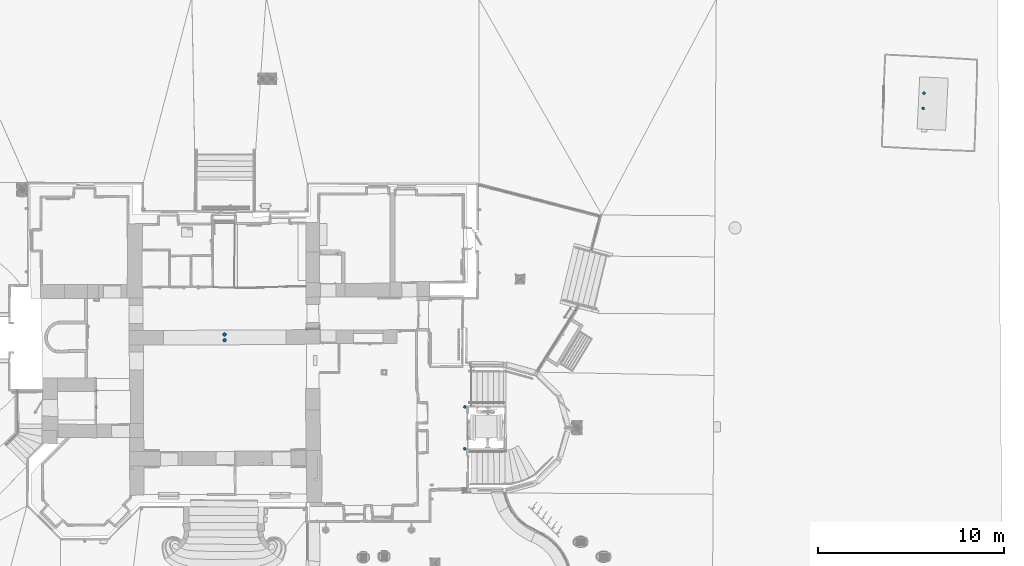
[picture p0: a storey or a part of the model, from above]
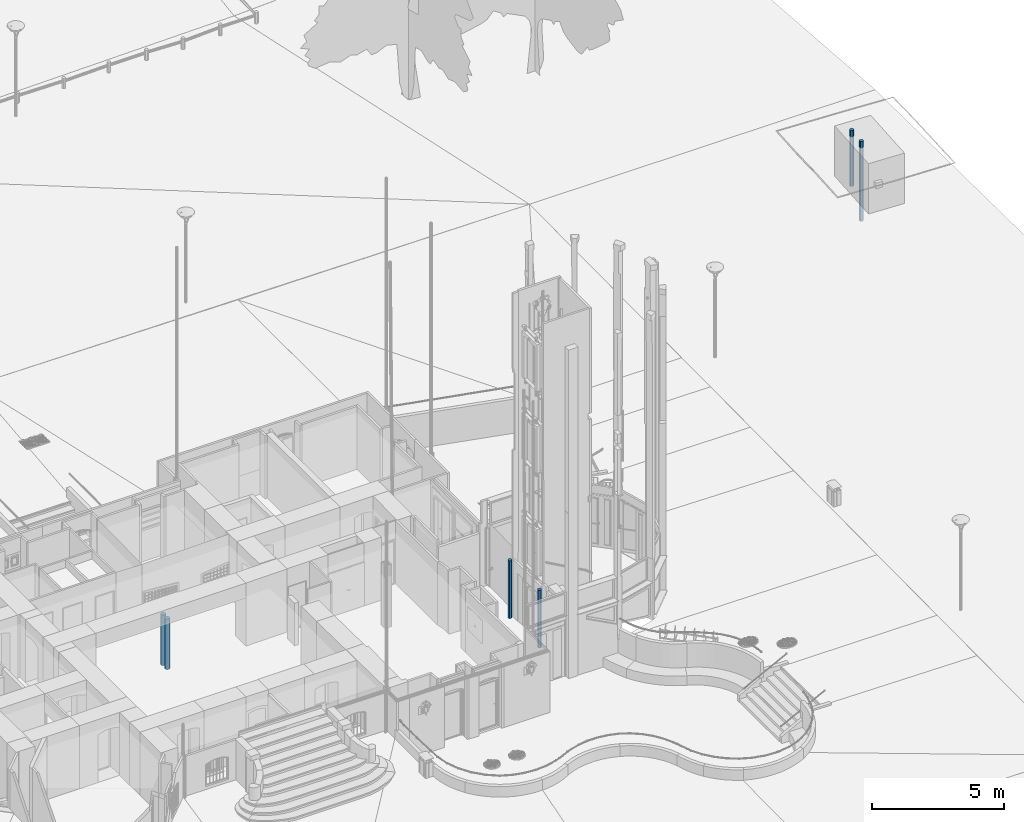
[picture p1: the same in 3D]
Properties of the parts of a building model (IFC2X3), part 1 of 37

# File
Description: ViewDefinition [CoordinationView_V2.0, QuantityTakeOffAddOnView]
File name: C:\Users\olivi\AppData\Local\Temp\EdificiusTmpDirDocs\DOC_739544-55453695\GUEUGNON Chateau d'Aux_2025 10 20.ifc
Time: 2025-10-20T15:24:24
Author: ingrid@planinsphere.com
Organization: Plan'In Sphère
Written by: ACCA_IFC.dll Version 500
Made in: ACCA Software S.p.A. - Edificius usBIM(o)

# IfcProject, GUEUGNON Chateau d'Aux_2025 10 14
IFC_PSET_Project - version: 2

# IfcSite, Default Site
RefLatitude: 0, 0, 0, 0; RefLongitude: 0, 0, 0, 0; RefElevation: 0 cm; Group: ...de matériaux et couleurs = Google Maps; ...de matériaux et couleurs - 1 = Terrain (01)
__RECOGNIZE__ - ID: 14967; TPLG: 1776; TPLG_OD: 1776; GENERATE: 1
CTLG_EXTERNAL_LINK - 0, DocType: 2; 0, Tag: 0; 0, Crc: 875694324; 1, DocType: 2; 1, Tag: 1; 1, Crc: -1747000580
IFC_PSET_PolygonOffset - polygonOffsetFactor: 2; polygonOffsetUnits: 2
IFC_Pset_Caractéristiques - ID: 14967; Numérotation: 01; Numéro niveau: 01; Titre niveau: Conception (1)
IFC_Pset_Données Métré - Volume Fouilles: 0 cm3; Volume Remblai: 0 cm3

# IfcBuildingStorey (8)
In: Default Building
Name | Description | Elevation (cm) | StateFlags | NominalHeight (cm)
TERRAIN | TERRAIN 2228 | -491.4 | 1 | 100
Fondation | Fondation 1046 | -391.4 | 2 | 100
Rez-de-Jardin | Rez-de-Jardin 15545 | -291.4 | 0 | 291.4
Rez-de-chaussée | Rez-de-chaussée 1047 | 0 | 0 | 477.795
Niveau 1 | Niveau 1 2343 | 477.795 | 0 | 376.115
Niveau 2 | Niveau 2 13545 | 853.91 | 0 | 235
Mezzanine | Mezzanine 49003 | 1088.91 | 0 | 279.702
Couverture | Couverture 2134 | 1368.61 | 4 | 0

# IfcSpace (78)
__RECOGNIZE__ - TPLG: 248; TPLG_OD: 9007; GENERATE: 1
CTLG_EXTERNAL_LINK - 0, DocType: 2; 0, Tag: 0; 0, Crc: -1342655586
IFC_PSET_PolygonOffset - polygonOffsetFactor: 1; polygonOffsetUnits: 1
IFC_Pset_Géométrie - Volume 3D: 0 cm3
IFC_Pset_Système de Référence Altimétrique_SUPÉRIEUR - delta: 0 cm; sous Niveau: <aucun>
IFC_Pset_Système de Référence Altimétrique_INFÉRIEUR - sous Niveau: <aucun>
IFC_Pset_Matériaux - Plancher: Pièce
Group: ...de matériaux et couleurs = Pièce
Name | In | Description = LongName = Nom = Reference | __RECOGNIZE__, ID = IFC_Pset_Caractéristiques, ID | Numérotation | Numéro niveau | Titre niveau | Aire (cm2) = Surface du Plafond (cm2) | Surface Nette (cm2) | Périmètre (cm) | Volume (cm3) | Hauteur (cm) = NominalHeight (cm) | Surface vitrée (cm2) | Rapport aéro-éclairant | Nombre de fenêtres | Nombre de portes | IFC_Pset_Système de Référence Altimétrique_SUPÉRIEUR, NIVEAU | IFC_Pset_Système de Référence Altimétrique_INFÉRIEUR, NIVEAU | delta (cm) | Périmètre du Plafond (cm) | GrossPlannedArea (cm2) = GrossFloorArea (cm2) = GrossCeilingArea (cm2) | GrossVolume (cm3) | GrossPerimeter (cm) | GrossWallArea (cm2) | NetWallArea (cm2)
Pièce 778369 | Rez-de-Jardin | PALIER ASC. RDJ | 778369 | 75 | 02 | Rez-de-Jardin | 177600 | 177200 | 3397.91 | 32930000 | 185.4 | 23975.2 | 0.135 | 2 | 3 | HAUT Rez-de-Jardin (Rez-de-chaussée 1047) | Rez-de-Jardin (Rez-de-Jardin 15545) | 106 | 3397.9 | 177606 | 32928213 | 3090.21 | 577951 | 362114
Pièce 590590 | Rez-de-Jardin | RANGEMENT 4 | 590590 | 69 | 02 | Rez-de-Jardin | 27300 | 27300 | 640.296 | 7940000 | 291.4 | 0 | 0 | 0 | 1 | HAUT Rez-de-Jardin (Rez-de-chaussée 1047) | Rez-de-Jardin (Rez-de-Jardin 15545) | 0 | 640.3 | 27251.4 | 7941082 | 640.296 | 142036 | 125761
Pièce 69640 | Rez-de-Jardin | LOCAL TECH.1 | 69640 | 18 | 02 | Rez-de-Jardin | 60200 | 60200 | 1158.9 | 17530000 | 291.4 | 6481.79 | 0.108 | 1 | 1 | HAUT Rez-de-Jardin (Rez-de-chaussée 1047) | Rez-de-Jardin (Rez-de-Jardin 15545) | 0 | 1158.9 | 60165.7 | 17532315 | 1158.9 | 335148 | 311362
Pièce 69641 | Rez-de-Jardin | WC2 | 69641 | 19 | 02 | Rez-de-Jardin | 17200 | 17200 | 533.931 | 5000000 | 291.4 | 0 | 0 | 0 | 1 | HAUT Rez-de-Jardin (Rez-de-chaussée 1047) | Rez-de-Jardin (Rez-de-Jardin 15545) | 0 | 533.9 | 17162.3 | 5001105 | 533.931 | 155577 | 138075
Pièce 69639 | Rez-de-Jardin | SALLE D'ACTIVITE 3 | 69639 | 17 | 02 | Rez-de-Jardin | 225300 | 225300 | 2055.74 | 65660000 | 291.4 | 21275.9 | 0.094 | 2 | 1 | HAUT Rez-de-Jardin (Rez-de-chaussée 1047) | Rez-de-Jardin (Rez-de-Jardin 15545) | 0 | 2055.7 | 225337 | 65663398 | 2055.74 | 577256 | 534926
Pièce 69642 | Rez-de-Jardin | WC3 | 69642 | 20 | 02 | Rez-de-Jardin | 26800 | 26800 | 663.262 | 7820000 | 291.4 | 0 | 0 | 0 | 1 | HAUT Rez-de-Jardin (Rez-de-chaussée 1047) | Rez-de-Jardin (Rez-de-Jardin 15545) | 0 | 663.3 | 26838.3 | 7820679 | 663.262 | 190308 | 170340
Pièce 72407 | Rez-de-Jardin | COULOIR 2 | 72407 | 33 | 02 | Rez-de-Jardin | 17400 | 17400 | 530.801 | 5070000 | 291.4 | 0 | 0 | 0 | 2 | HAUT Rez-de-Jardin (Rez-de-chaussée 1047) | Rez-de-Jardin (Rez-de-Jardin 15545) | 0 | 530.8 | 17408.2 | 5072766 | 530.801 | 154675 | 117405
Pièce 73199 | Rez-de-Jardin | LOCAL ELEC. | 73199 | 34 | 02 | Rez-de-Jardin | 15100 | 15100 | 502.217 | 4400000 | 291.4 | 0 | 0 | 0 | 1 | HAUT Rez-de-Jardin (Rez-de-chaussée 1047) | Rez-de-Jardin (Rez-de-Jardin 15545) | 0 | 502.2 | 15087.3 | 4396448 | 502.217 | 146343 | 110678
Pièce 72126 | Rez-de-Jardin | SALLE D'ACTIVITES 2 | 72126 | 31 | 02 | Rez-de-Jardin | 752400 | 751700 | 3962.15 | 219240000 | 291.4 | 44445.2 | 0.059 | 2 | 4 | HAUT Rez-de-Jardin (Rez-de-chaussée 1047) | Rez-de-Jardin (Rez-de-Jardin 15545) | 0 | 3962.2 | 752357 | 219237072 | 3451.56 | 1075218 | 869430
Pièce 72386 | Rez-de-Jardin | RANGEMENT 1 | 72386 | 32 | 02 | Rez-de-Jardin | 56800 | 56800 | 1056.47 | 16560000 | 291.4 | 35324.8 | 0.622 | 3 | 0 | HAUT Rez-de-Jardin (Rez-de-chaussée 1047) | Rez-de-Jardin (Rez-de-Jardin 15545) | 0 | 1056.5 | 56830.8 | 16560509 | 1056.47 | 284682 | 249357
Pièce 73240 | Rez-de-Jardin | COULOIR 5 | 73240 | 35 | 02 | Rez-de-Jardin | 31000 | 31000 | 704.007 | 9030000 | 291.4 | 0 | 0 | 0 | 1 | HAUT Rez-de-Jardin (Rez-de-chaussée 1047) | Rez-de-Jardin (Rez-de-Jardin 15545) | 0 | 704 | 30973.1 | 9025578 | 704.007 | 205148 | 125032
Pièce 77719 | Rez-de-Jardin | ZONE 1 | 77719 | 36 | 02 | Rez-de-Jardin | 220500 | 219900 | 6271.23 | 64240000 | 291.4 | 38357.6 | 0.174 | 3 | 1 | HAUT Rez-de-Jardin (Rez-de-chaussée 1047) | Rez-de-Jardin (Rez-de-Jardin 15545) | 0 | 6271.2 | 220466 | 64243867 | 5943.92 | 1734658 | 1611235
Pièce 78714 | Rez-de-Jardin | COULOIR 3 | 78714 | 37 | 02 | Rez-de-Jardin | 44600 | 44600 | 550.856 | 13010000 | 291.4 | 0 | 0 | 0 | 2 | HAUT Rez-de-Jardin (Rez-de-chaussée 1047) | Rez-de-Jardin (Rez-de-Jardin 15545) | 0 | 550.9 | 44639.8 | 13008065 | 550.856 | 285265 | 242583
Pièce 72125 | Rez-de-Jardin | COULOIR 4 | 72125 | 30 | 02 | Rez-de-Jardin | 95300 | 95300 | 1334.77 | 27780000 | 291.4 | 0 | 0 | 0 | 2 | HAUT Rez-de-Jardin (Rez-de-chaussée 1047) | Rez-de-Jardin (Rez-de-Jardin 15545) | 0 | 1334.8 | 95343 | 27782979 | 1334.77 | 384636 | 263139
Pièce 69646 | Rez-de-Jardin | COULOIR 1 | 69646 | 23 | 02 | Rez-de-Jardin | 92300 | 92300 | 1399.65 | 26890000 | 291.4 | 0 | 0 | 0 | 5 | HAUT Rez-de-Jardin (Rez-de-chaussée 1047) | Rez-de-Jardin (Rez-de-Jardin 15545) | 0 | 1399.6 | 92283.6 | 26891473 | 1399.65 | 396507 | 271984
Pièce 69647 | Rez-de-Jardin | SALLE D'ACTIVITES 1 | 69647 | 24 | 02 | Rez-de-Jardin | 451000 | 450200 | 3303.92 | 131430000 | 291.4 | 0 | 0 | 0 | 6 | HAUT Rez-de-Jardin (Rez-de-chaussée 1047) | Rez-de-Jardin (Rez-de-Jardin 15545) | 0 | 3303.9 | 451034 | 131431362 | 3186.56 | 832034 | 705352
Pièce 69644 | Rez-de-Jardin | LOCAL TECH.2 | 69644 | 21 | 02 | Rez-de-Jardin | 161800 | 161800 | 1777.22 | 47140000 | 291.4 | 0 | 0 | 0 | 1 | HAUT Rez-de-Jardin (Rez-de-chaussée 1047) | Rez-de-Jardin (Rez-de-Jardin 15545) | 0 | 1777.2 | 161760 | 47136934 | 1777.22 | 513166 | 481302
Pièce 69645 | Rez-de-Jardin | CUISINE | 69645 | 22 | 02 | Rez-de-Jardin | 176900 | 176900 | 1812.47 | 51540000 | 291.4 | 10335.9 | 0.058 | 1 | 2 | HAUT Rez-de-Jardin (Rez-de-chaussée 1047) | Rez-de-Jardin (Rez-de-Jardin 15545) | 0 | 1812.5 | 176859 | 51536824 | 1812.47 | 521539 | 469656
Pièce 69648 | Rez-de-Jardin | RANGEMENT 3 | 69648 | 25 | 02 | Rez-de-Jardin | 197700 | 197700 | 1816.96 | 57600000 | 291.4 | 21073.1 | 0.107 | 2 | 1 | HAUT Rez-de-Jardin (Rez-de-chaussée 1047) | Rez-de-Jardin (Rez-de-Jardin 15545) | 0 | 1817 | 197651 | 57595612 | 1816.96 | 520915 | 477846
Pièce 69651 | Rez-de-Jardin | HALL D'ENTREE | 69651 | 28 | 02 | Rez-de-Jardin | 60900 | 60900 | 1062.43 | 17740000 | 291.4 | 36449 | 0.599 | 1 | 2 | HAUT Rez-de-Jardin (Rez-de-chaussée 1047) | Rez-de-Jardin (Rez-de-Jardin 15545) | 0 | 1062.4 | 60883.1 | 17741344 | 1062.43 | 302132 | 194031
Pièce 72124 | Rez-de-Jardin | WC1 | 72124 | 29 | 02 | Rez-de-Jardin | 17300 | 17300 | 536.218 | 5050000 | 291.4 | 0 | 0 | 0 | 1 | HAUT Rez-de-Jardin (Rez-de-chaussée 1047) | Rez-de-Jardin (Rez-de-Jardin 15545) | 0 | 536.2 | 17340 | 5052868 | 536.218 | 156254 | 138194
Pièce 69649 | Rez-de-Jardin | ACCUEIL PUBLIC | 69649 | 26 | 02 | Rez-de-Jardin | 35600 | 35600 | 756.182 | 10370000 | 291.4 | 0 | 0 | 0 | 1 | HAUT Rez-de-Jardin (Rez-de-chaussée 1047) | Rez-de-Jardin (Rez-de-Jardin 15545) | 0 | 756.2 | 35581.6 | 10368492 | 756.182 | 209906 | 170097
Pièce 69650 | Rez-de-Jardin | RANGEMENT 2 | 69650 | 27 | 02 | Rez-de-Jardin | 72900 | 72900 | 1269.75 | 21250000 | 291.4 | 34974.6 | 0.48 | 3 | 1 | HAUT Rez-de-Jardin (Rez-de-chaussée 1047) | Rez-de-Jardin (Rez-de-Jardin 15545) | 0 | 1269.7 | 72927.7 | 21251158 | 1269.75 | 357255 | 300662
Pièce 773667 | Rez-de-chaussée | PARVIS RDC | 773667 | 71 | 03 | Rez-de-chaussée | 168400 | 168400 | 2188.11 | 80440000 | 477.783 | 0 | 0 | 0 | 0 | HAUT Rez-de-chaussée (Niveau 1 2343) | Rez-de-chaussée (Rez-de-chaussée 1047) | 0.0128504 | 2188.1 | 168367 | 80442995 | 2188.11 | 1035403 | 535409
Pièce 773668 | Rez-de-chaussée | PALIER ASC. RDC | 773668 | 72 | 03 | Rez-de-chaussée | 209800 | 209400 | 2489.8 | 35200000 | 167.795 | 67410.4 | 0.321 | 3 | 0 | HAUT Rez-de-chaussée (Niveau 1 2343) | Rez-de-chaussée (Rez-de-chaussée 1047) | 310 | 2489.8 | 209788 | 35201502 | 2186.67 | 400969 | 323102
Pièce 11482 | Rez-de-chaussée | WC 3 | 11482 | 13 | 03 | Rez-de-chaussée | 29000 | 29000 | 687.568 | 13880000 | 477.795 | 0 | 0 | 0 | 1 | HAUT Rez-de-chaussée (Niveau 1 2343) | Rez-de-chaussée (Rez-de-chaussée 1047) | 0 | 687.6 | 29041.3 | 13875799 | 687.568 | 241021 | 221659
Pièce 11611 | Rez-de-chaussée | RANGEMENT 1 | 11611 | 14 | 03 | Rez-de-chaussée | 45400 | 45400 | 1241.72 | 21710000 | 477.795 | 0 | 0 | 0 | 1 | HAUT Rez-de-chaussée (Niveau 1 2343) | Rez-de-chaussée (Rez-de-chaussée 1047) | 0 | 1241.7 | 45443.2 | 21712572 | 1241.72 | 501804 | 482007
Pièce 11288 | Rez-de-chaussée | SALLE D'ACTIVITE 2 | 11288 | 11 | 03 | Rez-de-chaussée | 200500 | 200500 | 1738.91 | 95780000 | 477.795 | 106073 | 0.529 | 3 | 1 | HAUT Rez-de-chaussée (Niveau 1 2343) | Rez-de-chaussée (Rez-de-chaussée 1047) | 0 | 1738.9 | 200466 | 95781710 | 1738.91 | 792242 | 657132
Pièce 11289 | Rez-de-chaussée | SALLE D'ACTIVITE1 | 11289 | 12 | 03 | Rez-de-chaussée | 391500 | 391500 | 2703.54 | 187040000 | 477.795 | 109480 | 0.28 | 3 | 2 | HAUT Rez-de-chaussée (Niveau 1 2343) | Rez-de-chaussée (Rez-de-chaussée 1047) | 0 | 2703.5 | 391466 | 187040854 | 2703.54 | 1209278 | 1044044
Pièce 42196 | Rez-de-chaussée | COULOIR 3 | 42196 | 15 | 03 | Rez-de-chaussée | 15700 | 15700 | 507.256 | 7500000 | 477.783 | 0 | 0 | 0 | 2 | HAUT Rez-de-chaussée (Niveau 1 2343) | Rez-de-chaussée (Rez-de-chaussée 1047) | 0.0128504 | 507.3 | 15699.3 | 7500869 | 507.256 | 173843 | 106140
Pièce 46048 | Rez-de-chaussée | COULOIR 2 | 46048 | 16 | 03 | Rez-de-chaussée | 105700 | 105700 | 1217.88 | 50510000 | 477.783 | 0 | 0 | 0 | 2 | HAUT Rez-de-chaussée (Niveau 1 2343) | Rez-de-chaussée (Rez-de-chaussée 1047) | 0.0128504 | 1217.9 | 105714 | 50508466 | 1217.88 | 600135 | 542391
Pièce 11287 | Rez-de-chaussée | RANGEMENT 2 | 11287 | 10 | 03 | Rez-de-chaussée | 482000 | 480600 | 23391.1 | 230300000 | 477.795 | 620857 | 1.288 | 17 | 4 | HAUT Rez-de-chaussée (Niveau 1 2343) | Rez-de-chaussée (Rez-de-chaussée 1047) | 0 | 23391.1 | 482002 | 230298425 | 23311.3 | 9950952 | 8181942
Pièce 3683 | Rez-de-chaussée | WC 1 | 3683 | 03 | 03 | Rez-de-chaussée | 15300 | 15300 | 499.002 | 7320000 | 477.795 | 0 | 0 | 0 | 1 | HAUT Rez-de-chaussée (Niveau 1 2343) | Rez-de-chaussée (Rez-de-chaussée 1047) | 0 | 499 | 15327.7 | 7323518 | 499.002 | 121755 | 107545
Pièce 11281 | Rez-de-chaussée | SALLE EXPO 3 | 11281 | 04 | 03 | Rez-de-chaussée | 334100 | 334100 | 2517.23 | 159640000 | 477.795 | 96238.4 | 0.288 | 3 | 3 | HAUT Rez-de-chaussée (Niveau 1 2343) | Rez-de-chaussée (Rez-de-chaussée 1047) | 0 | 2517.2 | 334122 | 159641772 | 2517.23 | 1088985 | 899908
Pièce 3672 | Rez-de-chaussée | SALLE EXPO 1 | 3672 | 01 | 03 | Rez-de-chaussée | 543700 | 543700 | 3172.6 | 259770000 | 477.795 | 134010 | 0.246 | 3 | 2 | HAUT Rez-de-chaussée (Niveau 1 2343) | Rez-de-chaussée (Rez-de-chaussée 1047) | 0 | 3172.6 | 543686 | 259770544 | 3172.6 | 1289069 | 989831
Pièce 3673 | Rez-de-chaussée | WC 2 | 3673 | 02 | 03 | Rez-de-chaussée | 15100 | 15100 | 495.598 | 7210000 | 477.795 | 0 | 0 | 0 | 1 | HAUT Rez-de-chaussée (Niveau 1 2343) | Rez-de-chaussée (Rez-de-chaussée 1047) | 0 | 495.6 | 15095.4 | 7212531 | 495.598 | 118201 | 103605
Pièce 11282 | Rez-de-chaussée | LOCAL TECH. | 11282 | 05 | 03 | Rez-de-chaussée | 29500 | 29500 | 692.361 | 14110000 | 477.795 | 0 | 0 | 0 | 1 | HAUT Rez-de-chaussée (Niveau 1 2343) | Rez-de-chaussée (Rez-de-chaussée 1047) | 0 | 692.4 | 29528.9 | 14108774 | 692.361 | 228056 | 210754
Pièce 11285 | Rez-de-chaussée | KITCHINETTE | 11285 | 08 | 03 | Rez-de-chaussée | 42500 | 42500 | 1016.37 | 20320000 | 477.795 | 0 | 0 | 0 | 1 | HAUT Rez-de-chaussée (Niveau 1 2343) | Rez-de-chaussée (Rez-de-chaussée 1047) | 0 | 1016.4 | 42536.2 | 20323577 | 1016.37 | 448063 | 431816
Pièce 11286 | Rez-de-chaussée | SALLE EXPO 2 | 11286 | 09 | 03 | Rez-de-chaussée | 536100 | 536100 | 3053.79 | 256170000 | 477.795 | 64189.1 | 0.12 | 2 | 2 | HAUT Rez-de-chaussée (Niveau 1 2343) | Rez-de-chaussée (Rez-de-chaussée 1047) | 0 | 3053.8 | 536144 | 256166888 | 3053.79 | 1213556 | 822975
Pièce 11283 | Rez-de-chaussée | COULOIR 1 | 11283 | 06 | 03 | Rez-de-chaussée | 124800 | 124800 | 1712.2 | 59620000 | 477.795 | 0 | 0 | 0 | 8 | HAUT Rez-de-chaussée (Niveau 1 2343) | Rez-de-chaussée (Rez-de-chaussée 1047) | 0 | 1712.2 | 124772 | 59615281 | 1712.2 | 518589 | 377767
Pièce 11284 | Rez-de-chaussée | BUREAU 1 | 11284 | 07 | 03 | Rez-de-chaussée | 242000 | 242000 | 2044.65 | 115630000 | 477.795 | 66360 | 0.274 | 2 | 1 | HAUT Rez-de-chaussée (Niveau 1 2343) | Rez-de-chaussée (Rez-de-chaussée 1047) | 0 | 2044.7 | 242009 | 115630737 | 2044.65 | 834522 | 736639
Pièce 120671 | Niveau 1 | DEGAGEMENT 1 | 120671 | 52 | 04 | Niveau 1 | 30200 | 30200 | 704.042 | 11380000 | 376.102 | 0 | 0 | 0 | 2 | HAUT Niveau 1 (Niveau 2 13545) | Niveau 1 (Niveau 1 2343) | 0.0128504 | 704 | 30246.5 | 11375764 | 703.45 | 220489 | 134417
Pièce 121282 | Niveau 1 | RANGEMENT 1 | 121282 | 53 | 04 | Niveau 1 | 15400 | 15400 | 588.48 | 5790000 | 376.102 | 0 | 0 | 0 | 1 | HAUT Niveau 1 (Niveau 2 13545) | Niveau 1 (Niveau 1 2343) | 0.0128504 | 588.5 | 15388.4 | 5787611 | 588.48 | 221327 | 182303
Pièce 115763 | Niveau 1 | KITCHINETTE | 115763 | 50 | 04 | Niveau 1 | 39700 | 39700 | 976.883 | 14930000 | 376.102 | 0 | 0 | 0 | 0 | HAUT Niveau 1 (Niveau 2 13545) | Niveau 1 (Niveau 1 2343) | 0.0128504 | 976.9 | 39697.6 | 14930339 | 976.883 | 354502 | 340722
Pièce 119074 | Niveau 1 | PALIER ETAGE 1 | 119074 | 51 | 04 | Niveau 1 | 217700 | 217700 | 2313.57 | 31590000 | 145.115 | 10632.6 | 0.049 | 2 | 0 | HAUT Niveau 1 (Niveau 2 13545) | Niveau 1 (Niveau 1 2343) | 231 | 2313.6 | 217710 | 31593018 | 2313.57 | 298027 | 283686
Pièce 121283 | Niveau 1 | POINT D'EAU | 121283 | 54 | 04 | Niveau 1 | 10200 | 10200 | 434.252 | 3820000 | 376.102 | 0 | 0 | 0 | 0 | HAUT Niveau 1 (Niveau 2 13545) | Niveau 1 (Niveau 1 2343) | 0.0128504 | 434.3 | 10165.2 | 3823142 | 434.252 | 163068 | 135056
Pièce 132686 | Niveau 1 | RANGEMENT 2 | 132686 | 55 | 04 | Niveau 1 | 50600 | 50600 | 909.567 | 19030000 | 376.102 | 13170.7 | 0.26 | 1 | 1 | HAUT Niveau 1 (Niveau 2 13545) | Niveau 1 (Niveau 1 2343) | 0.0128504 | 909.6 | 50604.9 | 19032630 | 909.567 | 342061 | 312098
Pièce 132687 | Niveau 1 | DEGAGEMENT 2 | 132687 | 56 | 04 | Niveau 1 | 39700 | 39700 | 890.582 | 5660000 | 142.615 | 0 | 0 | 0 | 0 | HAUT Niveau 1 (Niveau 2 13545) | Niveau 1 (Niveau 1 2343) | 233.5 | 890.6 | 39713.5 | 5663747 | 890.582 | 126227 | 126227
Pièce 103198 | Niveau 1 | COULOIR 2 | 103198 | 49 | 04 | Niveau 1 | 179400 | 179400 | 2763.26 | 67460000 | 376.102 | 35704.2 | 0.199 | 2 | 9 | HAUT Niveau 1 (Niveau 2 13545) | Niveau 1 (Niveau 1 2343) | 0.0128504 | 2763.3 | 179370 | 67461278 | 2763.26 | 823066 | 550650
Pièce 95094 | Niveau 1 | BUREAU 2 | 95094 | 42 | 04 | Niveau 1 | 129100 | 129100 | 1478.23 | 48550000 | 376.102 | 21276.3 | 0.165 | 1 | 3 | HAUT Niveau 1 (Niveau 2 13545) | Niveau 1 (Niveau 1 2343) | 0.0128504 | 1478.2 | 129078 | 48546639 | 1478.23 | 553756 | 477295
Pièce 95095 | Niveau 1 | BUREAU 1 | 95095 | 43 | 04 | Niveau 1 | 241000 | 241000 | 2044.25 | 90620000 | 376.102 | 43743.4 | 0.182 | 2 | 1 | HAUT Niveau 1 (Niveau 2 13545) | Niveau 1 (Niveau 1 2343) | 0.0128504 | 2044.2 | 240955 | 90623654 | 2044.26 | 752676 | 663531
Pièce 95092 | Niveau 1 | WC 3 | 95092 | 40 | 04 | Niveau 1 | 15700 | 15700 | 506.684 | 5900000 | 376.102 | 0 | 0 | 0 | 1 | HAUT Niveau 1 (Niveau 2 13545) | Niveau 1 (Niveau 1 2343) | 0.0128504 | 506.7 | 15678.2 | 5896588 | 506.684 | 137659 | 122475
Pièce 95093 | Niveau 1 | RESERVE BIBLIOTHEQUE | 95093 | 41 | 04 | Niveau 1 | 389800 | 389800 | 2764.99 | 146600000 | 376.102 | 70362.1 | 0.181 | 3 | 1 | HAUT Niveau 1 (Niveau 2 13545) | Niveau 1 (Niveau 1 2343) | 0.0128504 | 2765 | 389794 | 146602338 | 2764.99 | 1025225 | 913486
Pièce 95096 | Niveau 1 | SALLE D'ACTIVITE 3 | 95096 | 44 | 04 | Niveau 1 | 192400 | 192400 | 1597.17 | 72360000 | 376.102 | 60243.9 | 0.313 | 3 | 1 | HAUT Niveau 1 (Niveau 2 13545) | Niveau 1 (Niveau 1 2343) | 0.0128504 | 1597.2 | 192406 | 72364172 | 1597.17 | 599627 | 508114
Pièce 95099 | Niveau 1 | COULOIR 1 | 95099 | 47 | 04 | Niveau 1 | 112100 | 112100 | 1559.57 | 42180000 | 376.102 | 0 | 0 | 0 | 5 | HAUT Niveau 1 (Niveau 2 13545) | Niveau 1 (Niveau 1 2343) | 0.0128504 | 1559.6 | 112143 | 42177385 | 1559.57 | 521442 | 348595
Pièce 103197 | Niveau 1 | BUREAU 3 | 103197 | 48 | 04 | Niveau 1 | 202600 | 202600 | 2008.11 | 76200000 | 376.102 | 68975.5 | 0.34 | 4 | 2 | HAUT Niveau 1 (Niveau 2 13545) | Niveau 1 (Niveau 1 2343) | 0.0128504 | 2008.1 | 202613 | 76203241 | 2008.11 | 752930 | 637268
Pièce 95097 | Niveau 1 | SALLE D'ACTIVITE 2 | 95097 | 45 | 04 | Niveau 1 | 525800 | 525800 | 2969.7 | 197750000 | 376.102 | 130304 | 0.248 | 5 | 4 | HAUT Niveau 1 (Niveau 2 13545) | Niveau 1 (Niveau 1 2343) | 0.0128504 | 2969.7 | 525799 | 197754079 | 2969.7 | 1039293 | 818044
Pièce 95098 | Niveau 1 | SALLE D'ACTIVITE 1 | 95098 | 46 | 04 | Niveau 1 | 351400 | 351400 | 2724.83 | 132150000 | 376.102 | 74197.6 | 0.211 | 3 | 4 | HAUT Niveau 1 (Niveau 2 13545) | Niveau 1 (Niveau 1 2343) | 0.0128504 | 2724.8 | 351356 | 132145665 | 2724.83 | 950003 | 699752
Pièce 774971 | Niveau 1 | BALCON | 774971 | 73 | 04 | Niveau 1 | 168500 | 168500 | 2193.94 | 15350000 | 91.115 | 0 | 0 | 0 | 0 | HAUT Niveau 1 (Niveau 2 13545) | Niveau 1 (Niveau 1 2343) | 285 | 2193.9 | 168452 | 15348500 | 2193.94 | 198583 | 161113
Pièce 756289 | Niveau 1 | PALIER ASC. R1 | 756289 | 70 | 04 | Niveau 1 | 203800 | 203400 | 2441.27 | 76660000 | 376.102 | 160746 | 0.789 | 3 | 0 | HAUT Niveau 1 (Niveau 2 13545) | Niveau 1 (Niveau 1 2343) | 0.0128504 | 2441.3 | 203826 | 76659396 | 2141 | 922903 | 661538
Pièce 95090 | Niveau 1 | WC 1 | 95090 | 38 | 04 | Niveau 1 | 29400 | 29400 | 693.73 | 11040000 | 376.102 | 0 | 0 | 0 | 1 | HAUT Niveau 1 (Niveau 2 13545) | Niveau 1 (Niveau 1 2343) | 0.0128504 | 693.7 | 29361.7 | 11042993 | 693.73 | 220224 | 199908
Pièce 95091 | Niveau 1 | WC 2 | 95091 | 39 | 04 | Niveau 1 | 16300 | 16300 | 515.818 | 6150000 | 376.102 | 0 | 0 | 0 | 1 | HAUT Niveau 1 (Niveau 2 13545) | Niveau 1 (Niveau 1 2343) | 0.0128504 | 515.8 | 16348.8 | 6148829 | 515.818 | 140976 | 125792
Pièce 152177 | Niveau 2 | WC 1 | 152177 | 57 | 05 | Niveau 2 | 29400 | 29400 | 692.673 | 6900000 | 235 | 0 | 0 | 0 | 1 | HAUT Niveau 2 (Mezzanine 49003) | Niveau 2 (Niveau 2 13545) | 3.55271e-13 | 692.7 | 29360.6 | 6899731 | 692.673 | 143901 | 124147
Pièce 152178 | Niveau 2 | WC 2 | 152178 | 58 | 05 | Niveau 2 | 16600 | 16600 | 519.931 | 460000 | 27.7035 | 0 | 0 | 0 | 0 | HAUT Niveau 2 (Mezzanine 49003) | Niveau 2 (Niveau 2 13545) | 207.296 | 519.9 | 16554.7 | 458624 | 519.931 | 3555.55 | 3555.55
Pièce 152179 | Niveau 2 | WC 3 | 152179 | 59 | 05 | Niveau 2 | 16200 | 16200 | 514.297 | 450000 | 27.7035 | 0 | 0 | 0 | 0 | HAUT Niveau 2 (Mezzanine 49003) | Niveau 2 (Niveau 2 13545) | 207.296 | 514.3 | 16154.1 | 447527 | 514.297 | 4747.29 | 4747.29
Pièce 777386 | Niveau 2 | PALIER ASC N2 | 777386 | 74 | 05 | Niveau 2 | 256500 | 256100 | 3150.24 | 60270000 | 235 | 103325 | 0.403 | 3 | 2 | HAUT Niveau 2 (Mezzanine 49003) | Niveau 2 (Niveau 2 13545) | 0 | 3150.2 | 256473 | 60271045 | 2841.49 | 696991 | 544657
Pièce 175456 | Niveau 2 | BUREAU | 175456 | 62 | 05 | Niveau 2 | 232700 | 232700 | 1933.4 | 1630000 | 7 | 0 | 0 | 0 | 0 | HAUT Niveau 2 (Mezzanine 49003) | Niveau 2 (Niveau 2 13545) | 228 | 1933.4 | 232711 | 1628975 | 1942.85 | 36599.3 | 36599.3
Pièce 175457 | Niveau 2 | STOCKAGE | 175457 | 63 | 05 | Niveau 2 | 194700 | 194700 | 1704.92 | 45760000 | 235 | 31187.6 | 0.16 | 2 | 1 | HAUT Niveau 2 (Mezzanine 49003) | Niveau 2 (Niveau 2 13545) | 3.55271e-13 | 1704.9 | 194740 | 45763972 | 1704.92 | 392531 | 345197
Pièce 152383 | Niveau 2 | COULOIR 1 | 152383 | 60 | 05 | Niveau 2 | 155500 | 155500 | 2361.28 | 36540000 | 235 | 20168.3 | 0.13 | 1 | 7 | HAUT Niveau 2 (Mezzanine 49003) | Niveau 2 (Niveau 2 13545) | 3.55271e-13 | 2361.3 | 155510 | 36544852 | 2361.32 | 446852 | 288865
Pièce 152875 | Niveau 2 | SALLE 2 | 152875 | 61 | 05 | Niveau 2 | 381300 | 381300 | 2713.69 | 89620000 | 235 | 32029.3 | 0.084 | 2 | 2 | HAUT Niveau 2 (Mezzanine 49003) | Niveau 2 (Niveau 2 13545) | 3.55271e-13 | 2713.7 | 381345 | 89616086 | 2713.69 | 591999 | 505296
Pièce 176757 | Niveau 2 | KITCHINETTE | 176757 | 64 | 05 | Niveau 2 | 46100 | 46100 | 1034.88 | 10830000 | 235 | 0 | 0 | 0 | 0 | HAUT Niveau 2 (Mezzanine 49003) | Niveau 2 (Niveau 2 13545) | 3.55271e-13 | 1034.9 | 46087.5 | 10830571 | 1034.88 | 221082 | 205742
Pièce 176921 | Niveau 2 | PALIER ETAGE 2 | 176921 | 65 | 05 | Niveau 2 | 58800 | 58700 | 925.654 | 13810000 | 235 | 8416.86 | 0.143 | 2 | 1 | HAUT Niveau 2 (Mezzanine 49003) | Niveau 2 (Niveau 2 13545) | 3.55271e-13 | 925.7 | 58750.9 | 13806459 | 916.723 | 268450 | 240201
Pièce 177562 | Niveau 2 | SALLE 1 | 177562 | 66 | 05 | Niveau 2 | 1810200 | 1775100 | 10677 | 18100000 | 10 | 0 | 0 | 0 | 0 | HAUT Niveau 2 (Mezzanine 49003) | Niveau 2 (Niveau 2 13545) | 225 | 10677 | 1810222 | 18102217 | 8689.91 | 99793.6 | 99793.6
Pièce 2032055 | Mezzanine | SALLE 3 | 2032055 | 78 | 06 | Mezzanine | 138300 | 138200 | 349.171 | 38690000 | 279.702 | 0 | 0 | 0 | 0 | HAUT Mezzanine (Couverture 2134) | Mezzanine (Mezzanine 49003) | 0 | 349.2 | 138320 | 38688549 | 0 | 489057 | 489057
Pièce 2041841 | Mezzanine | SALLE 4 | 2041841 | 79 | 06 | Mezzanine | 41900 | 41900 | 580.689 | 9620000 | 229.702 | 0 | 0 | 0 | 0 | HAUT Mezzanine (Couverture 2134) | Mezzanine (Mezzanine 49003) | 50 | 580.7 | 41890.6 | 9622368 | 580.689 | 148029 | 148029
Pièce 2027983 | Mezzanine | SALLE 1 | 2027983 | 76 | 06 | Mezzanine | 467800 | 467100 | 2939.37 | 130850000 | 279.702 | 0 | 0 | 0 | 1 | HAUT Mezzanine (Couverture 2134) | Mezzanine (Mezzanine 49003) | 0 | 2939.4 | 467801 | 130845064 | 2653.83 | 540788 | 523562
Pièce 2032054 | Mezzanine | SALLE 2 | 2032054 | 77 | 06 | Mezzanine | 175800 | 175200 | 1872.93 | 40730000 | 231.702 | 0 | 0 | 0 | 6 | HAUT Mezzanine (Couverture 2134) | Mezzanine (Mezzanine 49003) | 48 | 1872.9 | 175788 | 40730616 | 1589.51 | 312706 | 263550
Pièce 226787 | Mezzanine | LOCAL TECHN. | 226787 | 68 | 06 | Mezzanine | 86600 | 86400 | 1203.68 | 24230000 | 279.702 | 0 | 0 | 0 | 1 | HAUT Mezzanine (Couverture 2134) | Mezzanine (Mezzanine 49003) | 3.55271e-13 | 1203.7 | 86628.2 | 24230108 | 1000.98 | 196624 | 180657

# IfcBeam: 120x220 (2)
In: Niveau 2
Type - Material: Chêne
Description: Poutre; Group: ...de sections pour tiges = 120x220; ...de matériaux et couleurs = Chêne
__RECOGNIZE__ - TPLG: 210; TPLG_OD: 501; GENERATE: 1; Section_TypeForm: 0; AngleRotaz: 0; Section, Section_NumItems: 1; Section, Section_Item 0, Section_ID: 150; Section, Section_Item 0, Section_Desc: 120,00x220,00; Section, Section_Item 0, Section_Categ: 3; Section, Section_Item 0, Section_Tipo: 0; Section, Section_Item 0, Section_Base: 0.12; Section, Section_Item 0, Section_H: 0.22; Section, Section_Item 0, Section_DistPrfX: 0; Section, Section_Item 0, Section_DistPrfY: 0; Section, Section_Item 0, Section_DispInPianta: 0; Section, Section_Item 0, Section_TipoForma: 0; Section, Section_Item 0, Section_AngleRot: 0; Section, Section_Item 0, Section_BrcX: 0; Section, Section_Item 0, Section_BrcY: 0
CTLG_EXTERNAL_LINK - 0, DocType: 6; 0, Tag: -10; 0, Crc: -2138622633; 1, DocType: 2; 1, Tag: 0; 1, Crc: -1156274542
IFC_PSET_PolygonOffset - polygonOffsetFactor: 2; polygonOffsetUnits: 2
IFC_Pset_Alignment - Alignment_Sez: 0; Alignment_Poly: 0; Alignment_NODO_CLC: 0; Alignment_C_FC_SUP: 0
IFC_Pset_Caractéristiques - Numéro niveau: 05; Titre niveau: Niveau 2; Coupe: 120x220
IFC_Pset_Géométrie - Rotation: 0 deg
IFC_Pset_Géométrie_P1 (POINT initial) - Cote: -5 cm
IFC_Pset_Géométrie_P2 (POINT final) - Cote: -5 cm
IFC_Pset_Système de Référence Altimétrique_SUPÉRIEUR - NIVEAU: HAUT Niveau 2 (Mezzanine 49003); delta (P1): -5 cm; delta (P2): -5 cm; sous Niveau: <aucun>
IFC_Pset_Données Métré - Surface de la Section: 300 cm2; Base Section: 12 cm; Hauteur Section: 22 cm; Diamètre Section: 0 cm
IFC_Pset_Matériaux - Principal: Chêne
Pset_BeamCommon - Reference: 120x220 (..\Section rectangulaire\)
BaseQuantities - CrossSectionArea: 264 cm2
Name | __RECOGNIZE__, ID = IFC_Pset_Caractéristiques, ID | Alignment_Nodo | Alignment_TS | Numérotation | IFC_Pset_Géométrie_P1 (POINT initial), Longueur (cm) = IFC_Pset_Géométrie_P2 (POINT final), Longueur (cm) = Span (cm) = NominalLength (cm) | IFC_Pset_Géométrie_P1 (POINT initial), Angle XY (deg) | IFC_Pset_Géométrie_P2 (POINT final), Angle XY (deg) | Surface (latérale) (cm2) | Volume (cm3) | Slope (deg) | OuterSurfaceArea (cm2) | TotalSurfaceArea (cm2) | GrossVolume (cm3) = NetVolume (cm3)
Poutre 220051 | 220051 | 3 | 1 | 002 | 816.536 | 0.415524 | 180.416 | 55500 | 220000 | 0 | 55524.4 | 56052.4 | 215565
Poutre 219733 | 219733 | 0 | 0 | 001 | 905.45 | 0.492415 | 180.492 | 61600 | 240000 | 2.20695e-32 | 61570.6 | 62098.6 | 239039

# IfcBeam: 120x220, Poutre 1819848
In: Mezzanine
Type - Material: Eyong
Description: Poutre; Group: ...de matériaux et couleurs = Eyong; ...de sections pour tiges = 120x220
__RECOGNIZE__ - ID: 1819848; TPLG: 210; TPLG_OD: 501; GENERATE: 1; Section_TypeForm: 0; AngleRotaz: 0; Section, Section_NumItems: 1; Section, Section_Item 0, Section_ID: 150; Section, Section_Item 0, Section_Desc: 120,00x220,00; Section, Section_Item 0, Section_Categ: 3; Section, Section_Item 0, Section_Tipo: 0; Section, Section_Item 0, Section_Base: 0.12; Section, Section_Item 0, Section_H: 0.22; Section, Section_Item 0, Section_DistPrfX: 0; Section, Section_Item 0, Section_DistPrfY: 0; Section, Section_Item 0, Section_DispInPianta: 0; Section, Section_Item 0, Section_TipoForma: 0; Section, Section_Item 0, Section_AngleRot: 0; Section, Section_Item 0, Section_BrcX: 0; Section, Section_Item 0, Section_BrcY: 0
CTLG_EXTERNAL_LINK - 0, DocType: 2; 0, Tag: 0; 0, Crc: 1459353355; 1, DocType: 6; 1, Tag: -10; 1, Crc: -2138622633
IFC_PSET_PolygonOffset - polygonOffsetFactor: 2; polygonOffsetUnits: 2
IFC_Pset_Alignment - Alignment_Sez: 0; Alignment_Poly: 0; Alignment_Nodo: 3; Alignment_TS: 1; Alignment_NODO_CLC: 0; Alignment_C_FC_SUP: 0
IFC_Pset_Caractéristiques - ID: 1819848; Numérotation: 094; Numéro niveau: 06; Titre niveau: Mezzanine; Coupe: 120x220
IFC_Pset_Géométrie - Rotation: 0 deg
IFC_Pset_Géométrie_P1 (POINT initial) - Longueur: 336.104 cm; Cote: -66 cm; Angle XY: 0.00000170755 deg
IFC_Pset_Géométrie_P2 (POINT final) - Longueur: 336.104 cm; Cote: -272.4 cm; Angle XY: 180 deg
IFC_Pset_Système de Référence Altimétrique_SUPÉRIEUR - NIVEAU: HAUT Mezzanine (Couverture 2134); delta (P1): -66 cm; delta (P2): -272.4 cm; sous Niveau: <aucun>
IFC_Pset_Données Métré - Surface (latérale): 22900 cm2; Surface de la Section: 300 cm2; Volume: 90000 cm3; Base Section: 12 cm; Hauteur Section: 22 cm; Diamètre Section: 0 cm
IFC_Pset_Matériaux - Principal: Eyong
Pset_BeamCommon - Reference: 120x220 (..\Section rectangulaire\); Slope: -37.8863 deg; Span: 336.104 cm
BaseQuantities - NominalLength: 336.104 cm; CrossSectionArea: 264 cm2; OuterSurfaceArea: 22855.1 cm2; TotalSurfaceArea: 23383.1 cm2; GrossVolume: 88731.4 cm3; NetVolume: 88731.4 cm3

# IfcBeam: 127x127 (2)
In: Couverture
Type - Material: Aluminium mat
Description: Poutre en Acier; Group: ...de matériaux et couleurs = Aluminium mat; ...de profilés en acier = 127x127
__RECOGNIZE__ - TPLG: 214; TPLG_OD: 503; GENERATE: 1; Section_TypeForm: 0; AngleRotaz: 0.785398; Section, Section_NumItems: 1; Section, Section_Item 0, Section_ID: 258; Section, Section_Item 0, Section_Desc: 5X3-1/2; Section, Section_Item 0, Section_Categ: 2; Section, Section_Item 0, Section_Tipo: 22; Section, Section_Item 0, Section_Base: 0.127; Section, Section_Item 0, Section_H: 0.127; Section, Section_Item 0, Section_DistPrfX: 0; Section, Section_Item 0, Section_DistPrfY: 0; Section, Section_Item 0, Section_DispInPianta: 0; Section, Section_Item 0, Section_TipoForma: 0; Section, Section_Item 0, Section_AngleRot: 0; Section, Section_Item 0, Section_BrcX: 0; Section, Section_Item 0, Section_BrcY: 0
CTLG_EXTERNAL_LINK - 0, DocType: 2; 0, Tag: 0; 0, Crc: 913068333; 1, DocType: 7; 1, Tag: -10; 1, Crc: -2002251891
IFC_PSET_PolygonOffset - polygonOffsetFactor: 2; polygonOffsetUnits: 2
IFC_Pset_Alignment - Alignment_Sez: 0; Alignment_NODO_CLC: 0; Alignment_C_FC_SUP: 0
IFC_Pset_Caractéristiques - Numéro niveau: 07; Titre niveau: Couverture; Coupe: 127x127
IFC_Pset_Géométrie - Rotation: 0.785398 deg
IFC_Pset_Système de Référence Altimétrique_SUPÉRIEUR - NIVEAU: Couverture (Couverture 2134); sous Niveau: <aucun>
IFC_Pset_Données Métré - Surface de la Section: 161.3 cm2; Base Section: 12.7 cm; Hauteur Section: 12.7 cm; Diamètre Section: 0 cm
IFC_Pset_Matériaux - Principal: Aluminium mat
Pset_BeamCommon - Reference: 127x127 (..\Profilés\Rectangulaire vide arêtes vives\)
BaseQuantities - CrossSectionArea: 58.0644 cm2
Name | __RECOGNIZE__, ID = IFC_Pset_Caractéristiques, ID | Alignment_Poly | Alignment_Nodo | Alignment_TS | Numérotation | IFC_Pset_Géométrie_P1 (POINT initial), Longueur (cm) = IFC_Pset_Géométrie_P2 (POINT final), Longueur (cm) = Span (cm) = NominalLength (cm) | IFC_Pset_Géométrie_P1 (POINT initial), Cote (cm) = IFC_Pset_Géométrie_P2 (POINT final), Cote (cm) = delta (P1) (cm) = delta (P2) (cm) | IFC_Pset_Géométrie_P1 (POINT initial), Angle XY (deg) | IFC_Pset_Géométrie_P2 (POINT final), Angle XY (deg) | Surface (latérale) (cm2) | Volume (cm3) | Slope (deg) | OuterSurfaceArea (cm2) | TotalSurfaceArea (cm2) | GrossVolume (cm3) = NetVolume (cm3)
Poutre en Acier 1313591 | 1313591 | -200 | 6 | 1 | 065 | 632.487 | -182 | 90.1546 | 270.155 | 32130.3 | 36720 | -1.2424e-17 | 57834.6 | 57950.7 | 36725
Poutre en Acier 1313350 | 1313350 | 0 | -1 | 0 | 059 | 373.721 | -202 | 90.1789 | 270.179 | 17491.6 | 19990 | 0 | 34173.1 | 34289.2 | 21699.9

# IfcBeam: 130.0x160.0 (4)
In: Mezzanine
Type - Material: Eyong
Description: Poutre; Group: ...de matériaux et couleurs = Eyong; ...de sections pour tiges = 130.0x160.0
__RECOGNIZE__ - TPLG: 210; TPLG_OD: 501; GENERATE: 1; Section_TypeForm: 0; AngleRotaz: 0; Section, Section_NumItems: 1; Section, Section_Item 0, Section_ID: 174; Section, Section_Item 0, Section_Desc: 130,00x160,00; Section, Section_Item 0, Section_Categ: 3; Section, Section_Item 0, Section_Tipo: 0; Section, Section_Item 0, Section_Base: 0.13; Section, Section_Item 0, Section_H: 0.16; Section, Section_Item 0, Section_DistPrfX: 0; Section, Section_Item 0, Section_DistPrfY: 0; Section, Section_Item 0, Section_DispInPianta: 0; Section, Section_Item 0, Section_TipoForma: 0; Section, Section_Item 0, Section_AngleRot: 0; Section, Section_Item 0, Section_BrcX: 0; Section, Section_Item 0, Section_BrcY: 0
CTLG_EXTERNAL_LINK - 0, DocType: 2; 0, Tag: 0; 0, Crc: 1459353355; 1, DocType: 6; 1, Tag: -10; 1, Crc: -1011586244
IFC_PSET_PolygonOffset - polygonOffsetFactor: 2; polygonOffsetUnits: 2
IFC_Pset_Alignment - Alignment_Sez: 0; Alignment_Nodo: 3; Alignment_NODO_CLC: 0; Alignment_C_FC_SUP: 0
IFC_Pset_Caractéristiques - Numéro niveau: 06; Titre niveau: Mezzanine; Coupe: 130.0x160.0
IFC_Pset_Géométrie - Rotation: 0 deg
IFC_Pset_Système de Référence Altimétrique_SUPÉRIEUR - NIVEAU: HAUT Mezzanine (Couverture 2134); sous Niveau: <aucun>
IFC_Pset_Données Métré - Surface de la Section: 200 cm2; Base Section: 13 cm; Hauteur Section: 16 cm; Diamètre Section: 0 cm
IFC_Pset_Matériaux - Principal: Eyong
Pset_BeamCommon - Reference: 130.0x160.0 (..\Section rectangulaire\)
BaseQuantities - CrossSectionArea: 208 cm2
Name | __RECOGNIZE__, ID = IFC_Pset_Caractéristiques, ID | Alignment_Poly | Alignment_TS | Numérotation | IFC_Pset_Géométrie_P1 (POINT initial), Longueur (cm) = IFC_Pset_Géométrie_P2 (POINT final), Longueur (cm) = Span (cm) = NominalLength (cm) | IFC_Pset_Géométrie_P1 (POINT initial), Cote (cm) | IFC_Pset_Géométrie_P1 (POINT initial), Angle XY (deg) | IFC_Pset_Géométrie_P2 (POINT final), Cote (cm) = delta (P2) (cm) | IFC_Pset_Géométrie_P2 (POINT final), Angle XY (deg) | delta (P1) (cm) | Surface (latérale) (cm2) | Volume (cm3) | Slope (deg) | OuterSurfaceArea (cm2) | TotalSurfaceArea (cm2) | GrossVolume (cm3) = NetVolume (cm3)
Poutre 1819909 | 1819909 | 0 | 1 | 095 | 145.38 | -70.7481 | 4.7847 | -157 | 184.785 | -70.7481 | 8400 | 30000 | -36.3905 | 8432.05 | 8848.05 | 30239.1
Poutre 1884317 | 1884317 | -1 | 1 | 122 | 369.522 | -119.496 | 1.25345 | 200 | 181.253 | -119.496 | 21400 | 80000 | 59.8394 | 21432.2 | 21848.2 | 76860.5
Poutre 1883057 | 1883057 | -1 | 0 | 120 | 358.882 | -120 | 0 | 190 | 180 | -34.844 | 20800 | 70000 | 59.7453 | 20815.1 | 21231.1 | 74647.4
Poutre 1888246 | 1888246 | -1 | 0 | 123 | 359.935 | 190 | 0.557715 | -120 | 180.558 | -54.5349 | 20900 | 70000 | -59.459 | 20876.2 | 21292.2 | 74866.5

# IfcBeam: 140x200, Poutre 574864
In: Rez-de-Jardin
Type - Material: Béton (01)
Description: Poutre; Group: ...de matériaux et couleurs = Béton (01); ...de sections pour tiges = 140x200
__RECOGNIZE__ - ID: 574864; TPLG: 210; TPLG_OD: 501; GENERATE: 1; Section_TypeForm: 0; AngleRotaz: 0; Section, Section_NumItems: 1; Section, Section_Item 0, Section_ID: 146; Section, Section_Item 0, Section_Desc: 140,00x200,00; Section, Section_Item 0, Section_Categ: 3; Section, Section_Item 0, Section_Tipo: 0; Section, Section_Item 0, Section_Base: 0.14; Section, Section_Item 0, Section_H: 0.2; Section, Section_Item 0, Section_DistPrfX: 0; Section, Section_Item 0, Section_DistPrfY: 0; Section, Section_Item 0, Section_DispInPianta: 0; Section, Section_Item 0, Section_TipoForma: 0; Section, Section_Item 0, Section_AngleRot: 0; Section, Section_Item 0, Section_BrcX: 0; Section, Section_Item 0, Section_BrcY: 0
CTLG_EXTERNAL_LINK - 0, DocType: 2; 0, Tag: 0; 0, Crc: -1434640612; 1, DocType: 6; 1, Tag: -10; 1, Crc: 614355597
IFC_PSET_PolygonOffset - polygonOffsetFactor: 2; polygonOffsetUnits: 2
IFC_Pset_Alignment - Alignment_Sez: 0; Alignment_Poly: 0; Alignment_Nodo: 0; Alignment_TS: 0; Alignment_NODO_CLC: 0; Alignment_C_FC_SUP: 0
IFC_Pset_Caractéristiques - ID: 574864; Numérotation: 003; Numéro niveau: 02; Titre niveau: Rez-de-Jardin; Coupe: 140x200
IFC_Pset_Géométrie - Rotation: 0 deg
IFC_Pset_Géométrie_P1 (POINT initial) - Longueur: 203.636 cm; Cote: 82 cm; Angle XY: 90.1987 deg
IFC_Pset_Géométrie_P2 (POINT final) - Longueur: 203.636 cm; Cote: 82 cm; Angle XY: 270.199 deg
IFC_Pset_Système de Référence Altimétrique_SUPÉRIEUR - NIVEAU: HAUT Rez-de-Jardin (Rez-de-chaussée 1047); delta (P1): 82 cm; delta (P2): 82 cm; sous Niveau: <aucun>
IFC_Pset_Données Métré - Surface (latérale): 13800 cm2; Surface de la Section: 300 cm2; Volume: 60000 cm3; Base Section: 14 cm; Hauteur Section: 20 cm; Diamètre Section: 0 cm
IFC_Pset_Matériaux - Principal: Béton (01)
Pset_BeamCommon - Reference: 140x200 (..\Section rectangulaire\); Slope: 0 deg; Span: 203.636 cm
BaseQuantities - NominalLength: 203.636 cm; CrossSectionArea: 280 cm2; OuterSurfaceArea: 13847.2 cm2; TotalSurfaceArea: 14407.2 cm2; GrossVolume: 57018.1 cm3; NetVolume: 57018.1 cm3

# IfcBeam: 140x200 (6)
In: Mezzanine
Type - Material: Eyong
Description: Poutre; Group: ...de matériaux et couleurs = Eyong; ...de sections pour tiges = 140x200
__RECOGNIZE__ - TPLG: 210; TPLG_OD: 501; GENERATE: 1; Section_TypeForm: 0; AngleRotaz: 0; Section, Section_NumItems: 1; Section, Section_Item 0, Section_ID: 146; Section, Section_Item 0, Section_Desc: 140,00x200,00; Section, Section_Item 0, Section_Categ: 3; Section, Section_Item 0, Section_Tipo: 0; Section, Section_Item 0, Section_Base: 0.14; Section, Section_Item 0, Section_H: 0.2; Section, Section_Item 0, Section_DistPrfX: 0; Section, Section_Item 0, Section_DistPrfY: 0; Section, Section_Item 0, Section_DispInPianta: 0; Section, Section_Item 0, Section_TipoForma: 0; Section, Section_Item 0, Section_AngleRot: 0; Section, Section_Item 0, Section_BrcX: 0; Section, Section_Item 0, Section_BrcY: 0
CTLG_EXTERNAL_LINK - 0, DocType: 2; 0, Tag: 0; 0, Crc: 1459353355; 1, DocType: 6; 1, Tag: -10; 1, Crc: 614355597
IFC_PSET_PolygonOffset - polygonOffsetFactor: 2; polygonOffsetUnits: 2
IFC_Pset_Alignment - Alignment_Sez: 0; Alignment_Poly: 0; Alignment_Nodo: 0; Alignment_NODO_CLC: 0; Alignment_C_FC_SUP: 0
IFC_Pset_Caractéristiques - Numéro niveau: 06; Titre niveau: Mezzanine; Coupe: 140x200
IFC_Pset_Géométrie - Rotation: 0 deg
IFC_Pset_Système de Référence Altimétrique_SUPÉRIEUR - NIVEAU: HAUT Mezzanine (Couverture 2134); sous Niveau: <aucun>
IFC_Pset_Données Métré - Surface de la Section: 300 cm2; Base Section: 14 cm; Hauteur Section: 20 cm; Diamètre Section: 0 cm
IFC_Pset_Matériaux - Principal: Eyong
Pset_BeamCommon - Reference: 140x200 (..\Section rectangulaire\)
BaseQuantities - CrossSectionArea: 280 cm2
Name | __RECOGNIZE__, ID = IFC_Pset_Caractéristiques, ID | Alignment_TS | Numérotation | IFC_Pset_Géométrie_P1 (POINT initial), Longueur (cm) = IFC_Pset_Géométrie_P2 (POINT final), Longueur (cm) = Span (cm) = NominalLength (cm) | IFC_Pset_Géométrie_P1 (POINT initial), Cote (cm) | IFC_Pset_Géométrie_P1 (POINT initial), Angle XY (deg) | IFC_Pset_Géométrie_P2 (POINT final), Cote (cm) = delta (P2) (cm) | IFC_Pset_Géométrie_P2 (POINT final), Angle XY (deg) | delta (P1) (cm) | Surface (latérale) (cm2) | Volume (cm3) | Slope (deg) | OuterSurfaceArea (cm2) | TotalSurfaceArea (cm2) | GrossVolume (cm3) = NetVolume (cm3)
Poutre 1809122 | 1809122 | 1 | 086 | 200 | 151.355 | 91.2145 | -23.5315 | 271.215 | 151.355 | 13600 | 60000 | -60.9781 | 13600 | 14160 | 56000
Poutre 1812017 | 1812017 | 0 | 089 | 180 | -28.9731 | 91.0481 | 124.842 | 271.048 | -28.9731 | 12200 | 50000 | 58.7078 | 12240 | 12800 | 50400
Poutre 1805559 | 1805559 | 1 | 085 | 125 | -23.5315 | 91.2145 | -130 | 271.215 | -23.5315 | 8500 | 40000 | -58.4021 | 8500.01 | 9060.01 | 35000.1
Poutre 1815186 | 1815186 | 0 | 090 | 132.366 | -139 | 90 | -23.7944 | 270 | -139 | 9000 | 40000 | 60.5001 | 9000.89 | 9560.89 | 37062.5
Poutre 1810550 | 1810550 | 1 | 087 | 293.609 | 126.698 | 91.2145 | -125 | 271.215 | -27.6084 | 20000 | 80000 | -59.0099 | 19965.4 | 20525.4 | 82210.4
Poutre 1819587 | 1819587 | 0 | 091 | 350 | -139 | 90 | 165.625 | 270 | -25.9148 | 23800 | 100000 | 60.5001 | 23800 | 24360 | 98000

# IfcBeam: 150.0x150.0x25.0 (2)
In: Mezzanine
Type - Material: Eyong
Description: Poutre; Group: ...de sections pour tiges = 150.0x150.0x25.0; ...de matériaux et couleurs = Eyong
__RECOGNIZE__ - TPLG: 210; TPLG_OD: 501; GENERATE: 1; Section_TypeForm: 0; Section, Section_NumItems: 1; Section, Section_Item 0, Section_ID: 124; Section, Section_Item 0, Section_Desc: 150x150; Section, Section_Item 0, Section_Categ: 3; Section, Section_Item 0, Section_Tipo: 22; Section, Section_Item 0, Section_Base: 0.15; Section, Section_Item 0, Section_H: 0.15; Section, Section_Item 0, Section_DistPrfX: 0; Section, Section_Item 0, Section_DistPrfY: 0; Section, Section_Item 0, Section_DispInPianta: 0; Section, Section_Item 0, Section_TipoForma: 0; Section, Section_Item 0, Section_AngleRot: 0; Section, Section_Item 0, Section_BrcX: 0; Section, Section_Item 0, Section_BrcY: 0
CTLG_EXTERNAL_LINK - 0, DocType: 2; 0, Tag: 0; 0, Crc: 1459353355; 1, DocType: 6; 1, Tag: -10; 1, Crc: -603927665
IFC_PSET_PolygonOffset - polygonOffsetFactor: 2; polygonOffsetUnits: 2
IFC_Pset_Alignment - Alignment_Sez: 0; Alignment_Poly: 0; Alignment_NODO_CLC: 0; Alignment_C_FC_SUP: 0
IFC_Pset_Caractéristiques - Numéro niveau: 06; Titre niveau: Mezzanine; Coupe: 150.0x150.0x25.0
IFC_Pset_Système de Référence Altimétrique_SUPÉRIEUR - NIVEAU: HAUT Mezzanine (Couverture 2134); sous Niveau: <aucun>
IFC_Pset_Données Métré - Surface de la Section: 200 cm2; Volume: 50000 cm3; Base Section: 15 cm; Hauteur Section: 15 cm; Diamètre Section: 0 cm
IFC_Pset_Matériaux - Principal: Eyong
Pset_BeamCommon - Reference: 150.0x150.0x25.0 (..\Section rectangulaire arrondie\)
BaseQuantities - CrossSectionArea: 219.607 cm2
Name | __RECOGNIZE__, ID = IFC_Pset_Caractéristiques, ID | AngleRotaz = Rotation (deg) | Alignment_Nodo | Alignment_TS | Numérotation | IFC_Pset_Géométrie_P1 (POINT initial), Longueur (cm) = IFC_Pset_Géométrie_P2 (POINT final), Longueur (cm) = Span (cm) = NominalLength (cm) | IFC_Pset_Géométrie_P1 (POINT initial), Cote (cm) | IFC_Pset_Géométrie_P1 (POINT initial), Angle XY (deg) | IFC_Pset_Géométrie_P2 (POINT final), Cote (cm) = delta (P2) (cm) | IFC_Pset_Géométrie_P2 (POINT final), Angle XY (deg) | delta (P1) (cm) | Surface (latérale) (cm2) | Slope (deg) | OuterSurfaceArea (cm2) | TotalSurfaceArea (cm2) | GrossVolume (cm3) = NetVolume (cm3)
Poutre 1819841 | 1819841 | 0.785398 | 1 | 1 | 093 | 236.71 | -163 | 90 | -163 | 270 | -163 | 13200 | 0 | 13186.6 | 13625.8 | 51983.2
Poutre 1780034 | 1780034 | 0 | 7 | 0 | 072 | 238.741 | -272.267 | 45.8919 | -91.5108 | 225.892 | -240.739 | 13300 | 49.2113 | 13299.8 | 13739 | 52429.2

# IfcBeam: 187x300 (17)
In: Mezzanine
Type - Material: Eyong
Description: Poutre; Group: ...de matériaux et couleurs = Eyong; ...de sections pour tiges = 187x300
__RECOGNIZE__ - TPLG: 210; TPLG_OD: 501; GENERATE: 1; Section_TypeForm: 0; AngleRotaz: 0; Section, Section_NumItems: 1; Section, Section_Item 0, Section_ID: 156; Section, Section_Item 0, Section_Desc: 187x300; Section, Section_Item 0, Section_Categ: 3; Section, Section_Item 0, Section_Tipo: 0; Section, Section_Item 0, Section_Base: 0.187; Section, Section_Item 0, Section_H: 0.3; Section, Section_Item 0, Section_DistPrfX: 0; Section, Section_Item 0, Section_DistPrfY: 0; Section, Section_Item 0, Section_DispInPianta: 0; Section, Section_Item 0, Section_TipoForma: 0; Section, Section_Item 0, Section_AngleRot: 0; Section, Section_Item 0, Section_BrcX: 0; Section, Section_Item 0, Section_BrcY: 0
CTLG_EXTERNAL_LINK - 0, DocType: 2; 0, Tag: 0; 0, Crc: 1459353355; 1, DocType: 6; 1, Tag: -10; 1, Crc: 2071014828
IFC_PSET_PolygonOffset - polygonOffsetFactor: 2; polygonOffsetUnits: 2
IFC_Pset_Alignment - Alignment_Sez: 0; Alignment_Poly: 0; Alignment_NODO_CLC: 0; Alignment_C_FC_SUP: 0
IFC_Pset_Caractéristiques - Numéro niveau: 06; Titre niveau: Mezzanine; Coupe: 187x300
IFC_Pset_Géométrie - Rotation: 0 deg
IFC_Pset_Système de Référence Altimétrique_SUPÉRIEUR - NIVEAU: HAUT Mezzanine (Couverture 2134); sous Niveau: <aucun>
IFC_Pset_Données Métré - Surface de la Section: 600 cm2; Base Section: 18.7 cm; Hauteur Section: 30 cm; Diamètre Section: 0 cm
IFC_Pset_Matériaux - Principal: Eyong
Pset_BeamCommon - Reference: 187x300 (..\Section rectangulaire\)
BaseQuantities - CrossSectionArea: 561 cm2
Name | __RECOGNIZE__, ID = IFC_Pset_Caractéristiques, ID | Alignment_Nodo | Alignment_TS | Numérotation | IFC_Pset_Géométrie_P1 (POINT initial), Longueur (cm) = IFC_Pset_Géométrie_P2 (POINT final), Longueur (cm) = Span (cm) = NominalLength (cm) | IFC_Pset_Géométrie_P1 (POINT initial), Cote (cm) | IFC_Pset_Géométrie_P1 (POINT initial), Angle XY (deg) | IFC_Pset_Géométrie_P2 (POINT final), Cote (cm) = delta (P2) (cm) | IFC_Pset_Géométrie_P2 (POINT final), Angle XY (deg) | delta (P1) (cm) | Surface (latérale) (cm2) | Volume (cm3) | Slope (deg) | OuterSurfaceArea (cm2) | TotalSurfaceArea (cm2) | GrossVolume (cm3) = NetVolume (cm3)
Poutre 1717275 | 1717275 | 0 | 1 | 056 | 98.758 | -270 | 0.797217 | -268 | 180.797 | -270 | 9600 | 60000 | 1.16041 | 9619.03 | 10741 | 55403.3
Poutre 1717274 | 1717274 | 0 | 1 | 055 | 103.8 | -268 | 0.797217 | -265 | 180.797 | -268 | 10100 | 60000 | 1.65618 | 10110.1 | 11232.1 | 58231.6
Poutre 1717774 | 1717774 | 3 | 0 | 059 | 108.72 | -230 | 135.047 | -230 | 315.047 | -230 | 10600 | 60000 | 0 | 10589.3 | 11711.3 | 60991.7
Poutre 1715116 | 1715116 | 0 | 1 | 037 | 128.403 | -265 | 44.4722 | -265 | 224.472 | -265 | 12500 | 70000 | 0 | 12506.4 | 13628.4 | 72033.9
Poutre 1715126 | 1715126 | 0 | 1 | 040 | 248.1 | -265 | 0.43893 | -260 | 180.439 | -265 | 24200 | 140000 | 1.15477 | 24164.9 | 25286.9 | 139184
Poutre 1715110 | 1715110 | 0 | 1 | 035 | 498.706 | -265 | 137.137 | -265 | 317.137 | -265 | 48600 | 280000 | 0 | 48573.9 | 49695.9 | 279774
Poutre 1717252 | 1717252 | 3 | 0 | 048 | 132.733 | -260 | 46.6887 | -260 | 226.689 | -260 | 12900 | 70000 | 0 | 12928.2 | 14050.2 | 74463.1
Poutre 1717249 | 1717249 | 0 | 1 | 047 | 131.712 | -260 | 135.716 | -260 | 315.716 | -260 | 12800 | 70000 | 0 | 12828.7 | 13950.7 | 73890.3
Poutre 1715130 | 1715130 | 0 | 1 | 041 | 532.023 | -265 | 43.8998 | -260.281 | 223.9 | -265 | 51800 | 300000 | 0.508235 | 51819 | 52941 | 298465
Poutre 1716385 | 1716385 | 0 | 0 | 044 | 501.254 | -261.078 | 43.5213 | -264 | 223.521 | -261.078 | 48800 | 280000 | -0.334005 | 48822.1 | 49944.1 | 281203
Poutre 1715102 | 1715102 | 0 | 1 | 034 | 445.591 | -270 | 0.797217 | -270 | 180.797 | -270 | 43400 | 250000 | 0 | 43400.5 | 44522.5 | 249976
Poutre 1715113 | 1715113 | 0 | 0 | 036 | 404.552 | -265.576 | 90.4124 | -263 | 270.412 | -264.995 | 39400 | 230000 | 0.364878 | 39403.4 | 40525.4 | 226954
Poutre 1715216 | 1715216 | 3 | 1 | 042 | 898.572 | -270 | 0.555365 | -270 | 180.555 | -270 | 87500 | 500000 | 0 | 87520.9 | 88642.9 | 504099
Poutre 1717020 | 1717020 | 3 | 1 | 045 | 527.218 | -260 | 137.073 | -260 | 317.073 | -260 | 51400 | 300000 | 0 | 51351 | 52473 | 295769
Poutre 1717259 | 1717259 | 0 | 1 | 052 | 212.645 | -260 | 46.6694 | -260 | 226.669 | -260 | 20700 | 120000 | 0 | 20711.6 | 21833.6 | 119294
Poutre 1717170 | 1717170 | 0 | 1 | 046 | 398.333 | -260 | 90.4992 | -260 | 270.499 | -260 | 38800 | 220000 | 0 | 38797.6 | 39919.6 | 223465
Poutre 1715120 | 1715120 | 3 | 1 | 038 | 128.205 | -265 | 135.872 | -265 | 315.872 | -265 | 12500 | 70000 | 0 | 12487.2 | 13609.2 | 71922.9

# IfcBeam: 200,00x200,00x10,00 (8)
Type - Material: Eyong
Description: Poutre; Group: ...de sections pour tiges = 200,00x200,00x10,00; ...de matériaux et couleurs = Eyong
__RECOGNIZE__ - TPLG: 210; TPLG_OD: 501; GENERATE: 1; Section_TypeForm: 0; AngleRotaz: 0; Section, Section_NumItems: 1; Section, Section_Item 0, Section_ID: 118; Section, Section_Item 0, Section_Desc: 200,00x200,00x10,00; Section, Section_Item 0, Section_Categ: 3; Section, Section_Item 0, Section_Tipo: 22; Section, Section_Item 0, Section_Base: 0.2; Section, Section_Item 0, Section_H: 0.2; Section, Section_Item 0, Section_DistPrfX: 0; Section, Section_Item 0, Section_DistPrfY: 0; Section, Section_Item 0, Section_DispInPianta: 0; Section, Section_Item 0, Section_TipoForma: 0; Section, Section_Item 0, Section_AngleRot: 0; Section, Section_Item 0, Section_BrcX: 0; Section, Section_Item 0, Section_BrcY: 0
CTLG_EXTERNAL_LINK - 0, DocType: 2; 0, Tag: 0; 0, Crc: 1459353355; 1, DocType: 6; 1, Tag: -10; 1, Crc: -579435193
IFC_PSET_PolygonOffset - polygonOffsetFactor: 2; polygonOffsetUnits: 2
IFC_Pset_Alignment - Alignment_Sez: 0; Alignment_Poly: 0; Alignment_TS: 1; Alignment_NODO_CLC: 0; Alignment_C_FC_SUP: 0
IFC_Pset_Caractéristiques - Coupe: 200,00x200,00x10,00
IFC_Pset_Géométrie - Rotation: 0 deg
IFC_Pset_Système de Référence Altimétrique_SUPÉRIEUR - sous Niveau: <aucun>
IFC_Pset_Données Métré - Surface de la Section: 400 cm2; Base Section: 20 cm; Hauteur Section: 20 cm; Diamètre Section: 0 cm
IFC_Pset_Matériaux - Principal: Eyong
Pset_BeamCommon - Reference: 200,00x200,00x10,00 (..\Section rectangulaire arrondie\); Slope: 0 deg
BaseQuantities - CrossSectionArea: 399.138 cm2
Name | In | __RECOGNIZE__, ID = IFC_Pset_Caractéristiques, ID | Alignment_Nodo | Numérotation | Numéro niveau | Titre niveau | IFC_Pset_Géométrie_P1 (POINT initial), Longueur (cm) = IFC_Pset_Géométrie_P2 (POINT final), Longueur (cm) = Span (cm) = NominalLength (cm) | IFC_Pset_Géométrie_P1 (POINT initial), Cote (cm) = IFC_Pset_Géométrie_P2 (POINT final), Cote (cm) = delta (P1) (cm) = delta (P2) (cm) | IFC_Pset_Géométrie_P1 (POINT initial), Angle XY (deg) | IFC_Pset_Géométrie_P2 (POINT final), Angle XY (deg) | NIVEAU | Surface (latérale) (cm2) | Volume (cm3) | OuterSurfaceArea (cm2) | TotalSurfaceArea (cm2) | GrossVolume (cm3) = NetVolume (cm3)
Poutre 1741656 | Niveau 2 | 1741656 | 2 | 070 | 05 | Niveau 2 | 40.4042 | 12 | 0 | 180 | HAUT Niveau 2 (Mezzanine 49003) | 3100 | 20000 | 3137.66 | 3935.94 | 16126.8
Poutre 1740831 | Niveau 2 | 1740831 | 7 | 067 | 05 | Niveau 2 | 35.4914 | 12 | 46.7742 | 226.774 | HAUT Niveau 2 (Mezzanine 49003) | 2800 | 10000 | 2756.15 | 3554.43 | 14166
Poutre 1740508 | Niveau 2 | 1740508 | 1 | 066 | 05 | Niveau 2 | 47.2721 | 12 | 136.71 | 316.71 | HAUT Niveau 2 (Mezzanine 49003) | 3700 | 20000 | 3671 | 4469.28 | 18868.1
Poutre 1741368 | Niveau 2 | 1741368 | 7 | 069 | 05 | Niveau 2 | 45.5346 | 12 | 137.232 | 317.232 | HAUT Niveau 2 (Mezzanine 49003) | 3500 | 20000 | 3536.08 | 4334.35 | 18174.6
Poutre 1741092 | Niveau 2 | 1741092 | 2 | 068 | 05 | Niveau 2 | 37.484 | 12 | 43.2132 | 223.213 | HAUT Niveau 2 (Mezzanine 49003) | 2900 | 10000 | 2910.89 | 3709.16 | 14961.3
Poutre 1720691 | Niveau 2 | 1720691 | 0 | 061 | 05 | Niveau 2 | 53.8111 | 20 | 123.369 | 303.369 | HAUT Niveau 2 (Mezzanine 49003) | 4200 | 20000 | 4178.8 | 4977.07 | 21478
Poutre 1719965 | Niveau 2 | 1719965 | 1 | 060 | 05 | Niveau 2 | 38.8211 | 19 | 90 | 270 | HAUT Niveau 2 (Mezzanine 49003) | 3000 | 20000 | 3014.72 | 3813 | 15495
Poutre 1741944 | Mezzanine | 1741944 | 2 | 071 | 06 | Mezzanine | 355.567 | -235 | 45.5411 | 225.541 | HAUT Mezzanine (Couverture 2134) | 27600 | 140000 | 27612.2 | 28410.5 | 141920

# IfcBeam: 240x200 (4)
In: Niveau 2
Type - Material: Eyong
Description: Poutre; Group: ...de matériaux et couleurs = Eyong; ...de sections pour tiges = 240x200
__RECOGNIZE__ - TPLG: 210; TPLG_OD: 501; GENERATE: 1; Section_TypeForm: 0; AngleRotaz: 0; Section, Section_NumItems: 1; Section, Section_Item 0, Section_ID: 154; Section, Section_Item 0, Section_Desc: 240,00x200,00; Section, Section_Item 0, Section_Categ: 3; Section, Section_Item 0, Section_Tipo: 0; Section, Section_Item 0, Section_Base: 0.24; Section, Section_Item 0, Section_H: 0.2; Section, Section_Item 0, Section_DistPrfX: 0; Section, Section_Item 0, Section_DistPrfY: 0; Section, Section_Item 0, Section_DispInPianta: 0; Section, Section_Item 0, Section_TipoForma: 0; Section, Section_Item 0, Section_AngleRot: 0; Section, Section_Item 0, Section_BrcX: 0; Section, Section_Item 0, Section_BrcY: 0
CTLG_EXTERNAL_LINK - 0, DocType: 2; 0, Tag: 0; 0, Crc: 1459353355; 1, DocType: 6; 1, Tag: -10; 1, Crc: -1373019717
IFC_PSET_PolygonOffset - polygonOffsetFactor: 2; polygonOffsetUnits: 2
IFC_Pset_Alignment - Alignment_Sez: 0; Alignment_Poly: 0; Alignment_NODO_CLC: 0; Alignment_C_FC_SUP: 0
IFC_Pset_Caractéristiques - Numéro niveau: 05; Titre niveau: Niveau 2; Coupe: 240x200
IFC_Pset_Géométrie - Rotation: 0 deg
IFC_Pset_Géométrie_P1 (POINT initial) - Cote: 12 cm
IFC_Pset_Géométrie_P2 (POINT final) - Cote: 12 cm
IFC_Pset_Système de Référence Altimétrique_SUPÉRIEUR - NIVEAU: HAUT Niveau 2 (Mezzanine 49003); delta (P1): 12 cm; delta (P2): 12 cm; sous Niveau: <aucun>
IFC_Pset_Données Métré - Surface de la Section: 500 cm2; Base Section: 24 cm; Hauteur Section: 20 cm; Diamètre Section: 0 cm
IFC_Pset_Matériaux - Principal: Eyong
Pset_BeamCommon - Reference: 240x200 (..\Section rectangulaire\)
BaseQuantities - CrossSectionArea: 480 cm2
Name | __RECOGNIZE__, ID = IFC_Pset_Caractéristiques, ID | Alignment_Nodo | Alignment_TS | Numérotation | IFC_Pset_Géométrie_P1 (POINT initial), Longueur (cm) = IFC_Pset_Géométrie_P2 (POINT final), Longueur (cm) = Span (cm) = NominalLength (cm) | IFC_Pset_Géométrie_P1 (POINT initial), Angle XY (deg) | IFC_Pset_Géométrie_P2 (POINT final), Angle XY (deg) | Surface (latérale) (cm2) | Volume (cm3) | Slope (deg) | OuterSurfaceArea (cm2) | TotalSurfaceArea (cm2) | GrossVolume (cm3) = NetVolume (cm3)
Poutre 1739741 | 1739741 | 3 | 0 | 065 | 61.0344 | 136.785 | 316.785 | 5400 | 30000 | 0 | 5371.03 | 6331.03 | 29296.5
Poutre 1734157 | 1734157 | 3 | 1 | 062 | 49.5337 | 46.5988 | 226.599 | 4400 | 20000 | 0 | 4358.97 | 5318.97 | 23776.2
Poutre 1738207 | 1738207 | 0 | 1 | 064 | 62.805 | 45 | 225 | 5500 | 30000 | 0 | 5526.84 | 6486.84 | 30146.4
Poutre 1736344 | 1736344 | 0 | 1 | 063 | 49.1221 | 136.41 | 316.41 | 4300 | 20000 | -1.41245e-30 | 4322.75 | 5282.75 | 23578.6

# IfcBeam: 280x280 (3)
In: Couverture
Type - Material: Aluminium mat
Description: Poutre en Acier; Group: ...de matériaux et couleurs = Aluminium mat; ...de profilés en acier = 280x280
__RECOGNIZE__ - TPLG: 214; TPLG_OD: 503; GENERATE: 1; Section_TypeForm: 0; AngleRotaz: 0; Section, Section_NumItems: 1; Section, Section_Item 0, Section_ID: 252; Section, Section_Item 0, Section_Desc: 280x280; Section, Section_Item 0, Section_Categ: 2; Section, Section_Item 0, Section_Tipo: 24; Section, Section_Item 0, Section_Base: 0.28; Section, Section_Item 0, Section_H: 0.28; Section, Section_Item 0, Section_DistPrfX: 0; Section, Section_Item 0, Section_DistPrfY: 0; Section, Section_Item 0, Section_DispInPianta: 0; Section, Section_Item 0, Section_TipoForma: 0; Section, Section_Item 0, Section_AngleRot: 0; Section, Section_Item 0, Section_BrcX: 0; Section, Section_Item 0, Section_BrcY: 0
CTLG_EXTERNAL_LINK - 0, DocType: 2; 0, Tag: 0; 0, Crc: 913068333; 1, DocType: 7; 1, Tag: -10; 1, Crc: -684708269
IFC_PSET_PolygonOffset - polygonOffsetFactor: 2; polygonOffsetUnits: 2
IFC_Pset_Alignment - Alignment_Sez: 0; Alignment_Poly: -200; Alignment_TS: 0; Alignment_NODO_CLC: 0; Alignment_C_FC_SUP: 0
IFC_Pset_Caractéristiques - Numéro niveau: 07; Titre niveau: Couverture; Coupe: 280x280
IFC_Pset_Géométrie - Rotation: 0 deg
IFC_Pset_Géométrie_P1 (POINT initial) - Cote: -270 cm
IFC_Pset_Géométrie_P2 (POINT final) - Cote: -270 cm
IFC_Pset_Système de Référence Altimétrique_SUPÉRIEUR - NIVEAU: Couverture (Couverture 2134); delta (P1): -270 cm; delta (P2): -270 cm; sous Niveau: <aucun>
IFC_Pset_Données Métré - Surface de la Section: 784 cm2; Base Section: 28 cm; Hauteur Section: 28 cm; Diamètre Section: 0 cm
IFC_Pset_Matériaux - Principal: Aluminium mat
Pset_BeamCommon - Reference: 280x280 (..\Profilés\Rectangulaire\); Slope: 0 deg
BaseQuantities - CrossSectionArea: 784 cm2
Name | __RECOGNIZE__, ID = IFC_Pset_Caractéristiques, ID | Alignment_Nodo | Numérotation | IFC_Pset_Géométrie_P1 (POINT initial), Longueur (cm) = IFC_Pset_Géométrie_P2 (POINT final), Longueur (cm) = Span (cm) = NominalLength (cm) | IFC_Pset_Géométrie_P1 (POINT initial), Angle XY (deg) | IFC_Pset_Géométrie_P2 (POINT final), Angle XY (deg) | Surface (latérale) (cm2) | Volume (cm3) | OuterSurfaceArea (cm2) | TotalSurfaceArea (cm2) | GrossVolume (cm3) = NetVolume (cm3)
Poutre en Acier 1303896 | 1303896 | 0 | 057 | 146.137 | 179.791 | 359.791 | 16367.4 | 114570 | 16367.4 | 17935.4 | 114572
Poutre en Acier 1312596 | 1312596 | 0 | 058 | 624.875 | 89.7268 | 269.727 | 69986 | 489900 | 69986 | 71554 | 489902
Poutre en Acier 1303097 | 1303097 | 6 | 056 | 592.082 | 90.1294 | 270.129 | 40532.1 | 283720 | 66313.1 | 67881.1 | 464192

# IfcBeam: 2X1-5/16 (7)
In: Mezzanine
Type - Material: Aluminium mat
Description: Poutre en Acier; Group: ...de matériaux et couleurs = Aluminium mat; ...de profilés en acier = 2X1-5/16
__RECOGNIZE__ - TPLG: 214; TPLG_OD: 503; GENERATE: 1; Section_TypeForm: 0; AngleRotaz: 0; Section, Section_NumItems: 1; Section, Section_Item 0, Section_ID: 274; Section, Section_Item 0, Section_Desc: 4X2-5/16; Section, Section_Item 0, Section_Categ: 2; Section, Section_Item 0, Section_Tipo: 22; Section, Section_Item 0, Section_Base: 0.025; Section, Section_Item 0, Section_H: 0.05; Section, Section_Item 0, Section_DistPrfX: 0; Section, Section_Item 0, Section_DistPrfY: 0; Section, Section_Item 0, Section_DispInPianta: 0; Section, Section_Item 0, Section_TipoForma: 0; Section, Section_Item 0, Section_AngleRot: 0; Section, Section_Item 0, Section_BrcX: 0; Section, Section_Item 0, Section_BrcY: 0
CTLG_EXTERNAL_LINK - 0, DocType: 2; 0, Tag: 0; 0, Crc: 913068333; 1, DocType: 7; 1, Tag: -10; 1, Crc: 745588298
IFC_PSET_PolygonOffset - polygonOffsetFactor: 2; polygonOffsetUnits: 2
IFC_Pset_Alignment - Alignment_Sez: 0; Alignment_Poly: -200; Alignment_Nodo: 4; Alignment_TS: 1; Alignment_NODO_CLC: 0; Alignment_C_FC_SUP: 0
IFC_Pset_Caractéristiques - Numéro niveau: 06; Titre niveau: Mezzanine; Coupe: 2X1-5/16
IFC_Pset_Géométrie - Rotation: 0 deg
IFC_Pset_Géométrie_P1 (POINT initial) - Longueur: 44.6329 cm; Angle XY: 179.717 deg
IFC_Pset_Géométrie_P2 (POINT final) - Longueur: 44.6329 cm; Angle XY: 359.717 deg
IFC_Pset_Système de Référence Altimétrique_SUPÉRIEUR - NIVEAU: HAUT Mezzanine (Couverture 2134); sous Niveau: <aucun>
IFC_Pset_Données Métré - Surface (latérale): 669.5 cm2; Surface de la Section: 12.5 cm2; Volume: 420 cm3; Base Section: 2.5 cm; Hauteur Section: 5 cm; Diamètre Section: 0 cm
IFC_Pset_Matériaux - Principal: Aluminium mat
Pset_BeamCommon - Reference: 2X1-5/16 (..\Profilés\Rectangulaire vide arêtes vives\); Slope: 0 deg; Span: 44.6329 cm
BaseQuantities - NominalLength: 44.6329 cm; CrossSectionArea: 9.3536 cm2; OuterSurfaceArea: 1056.91 cm2; TotalSurfaceArea: 1075.61 cm2; GrossVolume: 417.478 cm3; NetVolume: 417.478 cm3
Name | __RECOGNIZE__, ID = IFC_Pset_Caractéristiques, ID | Numérotation | IFC_Pset_Géométrie_P1 (POINT initial), Cote (cm) = IFC_Pset_Géométrie_P2 (POINT final), Cote (cm) = delta (P1) (cm) = delta (P2) (cm)
Poutre en Acier 1519636 | 1519636 | 076 | -475
Poutre en Acier 1519633 | 1519633 | 075 | -455
Poutre en Acier 1519644 | 1519644 | 077 | -495
Poutre en Acier 1519626 | 1519626 | 074 | -435
Poutre en Acier 1519599 | 1519599 | 071 | -395
Poutre en Acier 1519623 | 1519623 | 073 | -374
Poutre en Acier 1519620 | 1519620 | 072 | -415

# IfcBeam: 4X2-3/16 (8)
In: Couverture
Type - Material: Aluminium mat
Description: Poutre en Acier; Group: ...de matériaux et couleurs = Aluminium mat; ...de profilés en acier = 4X2-3/16
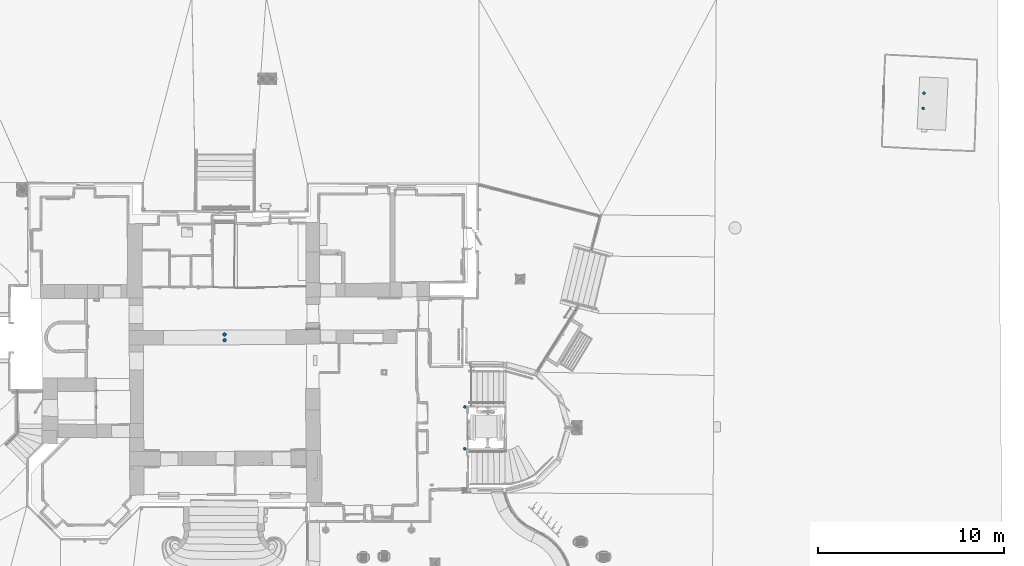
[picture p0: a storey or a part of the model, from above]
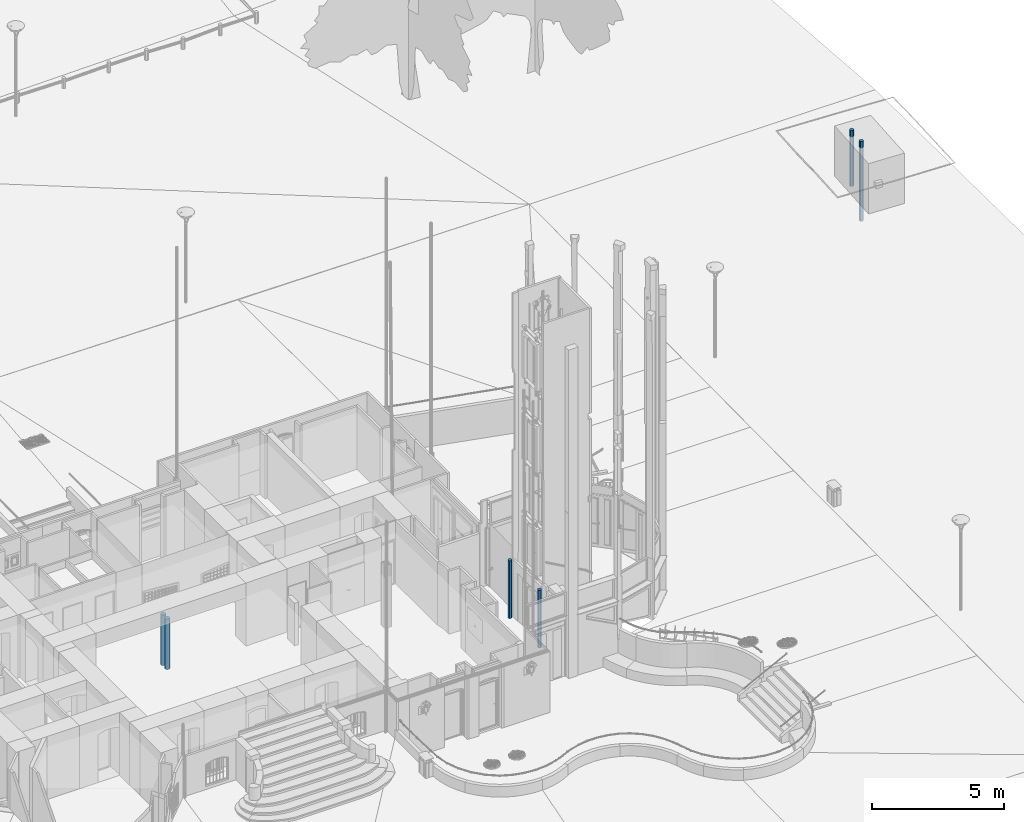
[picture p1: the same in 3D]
Properties of the parts of a building model (IFC2X3), part 2 of 37

# IfcBeam: 4X2-3/16 (8)
__RECOGNIZE__ - TPLG: 214; TPLG_OD: 503; GENERATE: 1; Section_TypeForm: 0; AngleRotaz: 0; Section, Section_NumItems: 1; Section, Section_Item 0, Section_ID: 272; Section, Section_Item 0, Section_Desc: 4X2-3/16; Section, Section_Item 0, Section_Categ: 2; Section, Section_Item 0, Section_Tipo: 22; Section, Section_Item 0, Section_Base: 0.0508; Section, Section_Item 0, Section_H: 0.1016; Section, Section_Item 0, Section_DistPrfX: 0; Section, Section_Item 0, Section_DistPrfY: 0; Section, Section_Item 0, Section_DispInPianta: 0; Section, Section_Item 0, Section_TipoForma: 0; Section, Section_Item 0, Section_AngleRot: 0; Section, Section_Item 0, Section_BrcX: 0; Section, Section_Item 0, Section_BrcY: 0
CTLG_EXTERNAL_LINK - 0, DocType: 2; 0, Tag: 0; 0, Crc: 913068333; 1, DocType: 7; 1, Tag: -10; 1, Crc: 73459728
IFC_PSET_PolygonOffset - polygonOffsetFactor: 2; polygonOffsetUnits: 2
IFC_Pset_Alignment - Alignment_Sez: 0; Alignment_Poly: -200; Alignment_NODO_CLC: 0; Alignment_C_FC_SUP: 0
IFC_Pset_Caractéristiques - Numéro niveau: 07; Titre niveau: Couverture; Coupe: 4X2-3/16
IFC_Pset_Géométrie - Rotation: 0 deg
IFC_Pset_Système de Référence Altimétrique_SUPÉRIEUR - NIVEAU: Couverture (Couverture 2134); sous Niveau: <aucun>
IFC_Pset_Données Métré - Surface de la Section: 51.6 cm2; Base Section: 5.1 cm; Hauteur Section: 10.2 cm; Diamètre Section: 0 cm
IFC_Pset_Matériaux - Principal: Aluminium mat
Pset_BeamCommon - Reference: 4X2-3/16 (..\Profilés\Rectangulaire vide arêtes vives\)
BaseQuantities - CrossSectionArea: 51.6128 cm2
Name | __RECOGNIZE__, ID = IFC_Pset_Caractéristiques, ID | Alignment_Nodo | Alignment_TS | Numérotation | IFC_Pset_Géométrie_P1 (POINT initial), Longueur (cm) = IFC_Pset_Géométrie_P2 (POINT final), Longueur (cm) = Span (cm) = NominalLength (cm) | IFC_Pset_Géométrie_P1 (POINT initial), Cote (cm) = delta (P1) (cm) | IFC_Pset_Géométrie_P1 (POINT initial), Angle XY (deg) | IFC_Pset_Géométrie_P2 (POINT final), Cote (cm) = delta (P2) (cm) | IFC_Pset_Géométrie_P2 (POINT final), Angle XY (deg) | Surface (latérale) (cm2) | Volume (cm3) | Slope (deg) | OuterSurfaceArea (cm2) | TotalSurfaceArea (cm2) | GrossVolume (cm3) = NetVolume (cm3)
Poutre en Acier 1313521 | 1313521 | 0 | 0 | 062 | 76.0898 | -200 | 0.0435875 | -255 | 180.044 | 2319.2 | 3930 | -46.2886 | 4346.25 | 4449.48 | 3927.21
Poutre en Acier 1313584 | 1313584 | 0 | 0 | 064 | 76.0898 | -200 | 0.0435875 | -255 | 180.044 | 2319.2 | 3930 | -46.2886 | 4346.25 | 4449.48 | 3927.21
Poutre en Acier 1313583 | 1313583 | 0 | 0 | 063 | 82.9998 | -259.525 | 0.018778 | -200 | 180.019 | 2529.8 | 4280 | 45.8217 | 4740.95 | 4844.18 | 4283.85
Poutre en Acier 1313361 | 1313361 | 0 | 0 | 060 | 82.9998 | -259.525 | 0.018778 | -200 | 180.019 | 2529.8 | 4280 | 45.8217 | 4740.95 | 4844.18 | 4283.85
Poutre en Acier 1314470 | 1314470 | 0 | 0 | 069 | 141.665 | -88.0897 | 90.3991 | -168 | 270.399 | 4318 | 7310 | -34.3383 | 8091.92 | 8195.15 | 7311.75
Poutre en Acier 1313610 | 1313610 | 6 | 1 | 066 | 86.9106 | -168 | 179.581 | -168 | 359.581 | 2649 | 4490 | 0 | 4964.33 | 5067.56 | 4485.7
Poutre en Acier 1313901 | 1313901 | 0 | 1 | 068 | 137.696 | -168 | 90.1331 | -87.6998 | 270.133 | 4197 | 7110 | 35.6738 | 7865.21 | 7968.43 | 7106.89
Poutre en Acier 1313615 | 1313615 | 0 | 1 | 067 | 88.1167 | -168 | 0.202473 | -168 | 180.202 | 2685.8 | 4550 | 0 | 5033.23 | 5136.45 | 4547.95

# IfcBeam: 4X2-5/16 (5)
In: Couverture
Type - Material: Aluminium mat
Description: Poutre en Acier; Group: ...de matériaux et couleurs = Aluminium mat; ...de profilés en acier = 4X2-5/16
__RECOGNIZE__ - TPLG: 214; TPLG_OD: 503; GENERATE: 1; Section_TypeForm: 0; Section, Section_NumItems: 1; Section, Section_Item 0, Section_ID: 270; Section, Section_Item 0, Section_Desc: 4X2-5/16; Section, Section_Item 0, Section_Categ: 2; Section, Section_Item 0, Section_Tipo: 22; Section, Section_Item 0, Section_Base: 0.0508; Section, Section_Item 0, Section_H: 0.1016; Section, Section_Item 0, Section_DistPrfX: 0; Section, Section_Item 0, Section_DistPrfY: 0; Section, Section_Item 0, Section_DispInPianta: 0; Section, Section_Item 0, Section_TipoForma: 0; Section, Section_Item 0, Section_AngleRot: 0; Section, Section_Item 0, Section_BrcX: 0; Section, Section_Item 0, Section_BrcY: 0
CTLG_EXTERNAL_LINK - 0, DocType: 2; 0, Tag: 0; 0, Crc: 913068333; 1, DocType: 7; 1, Tag: -10; 1, Crc: -1916063703
IFC_PSET_PolygonOffset - polygonOffsetFactor: 2; polygonOffsetUnits: 2
IFC_Pset_Alignment - Alignment_Sez: 0; Alignment_Poly: -200; Alignment_TS: 1; Alignment_NODO_CLC: 0; Alignment_C_FC_SUP: 0
IFC_Pset_Caractéristiques - Numéro niveau: 07; Titre niveau: Couverture; Coupe: 4X2-5/16
IFC_Pset_Système de Référence Altimétrique_SUPÉRIEUR - NIVEAU: Couverture (Couverture 2134); sous Niveau: <aucun>
IFC_Pset_Données Métré - Surface de la Section: 51.6 cm2; Base Section: 5.1 cm; Hauteur Section: 10.2 cm; Diamètre Section: 0 cm
IFC_Pset_Matériaux - Principal: Aluminium mat
Pset_BeamCommon - Reference: 4X2-5/16 (..\Profilés\Rectangulaire vide arêtes vives\); Slope: 0 deg
BaseQuantities - CrossSectionArea: 51.6128 cm2
Name | __RECOGNIZE__, ID = IFC_Pset_Caractéristiques, ID | AngleRotaz = Rotation (deg) | Alignment_Nodo | Numérotation | IFC_Pset_Géométrie_P1 (POINT initial), Longueur (cm) = IFC_Pset_Géométrie_P2 (POINT final), Longueur (cm) = Span (cm) = NominalLength (cm) | IFC_Pset_Géométrie_P1 (POINT initial), Cote (cm) = IFC_Pset_Géométrie_P2 (POINT final), Cote (cm) = delta (P1) (cm) = delta (P2) (cm) | IFC_Pset_Géométrie_P1 (POINT initial), Angle XY (deg) | IFC_Pset_Géométrie_P2 (POINT final), Angle XY (deg) | Surface (latérale) (cm2) | Volume (cm3) | OuterSurfaceArea (cm2) | TotalSurfaceArea (cm2) | GrossVolume (cm3) = NetVolume (cm3)
Poutre en Acier 1525433 | 1525433 | 0.785398 | 2 | 080 | 227.707 | -270 | 90.1294 | 270.129 | 6940.5 | 11750 | 12441.9 | 12545.1 | 11752.6
Poutre en Acier 1526463 | 1526463 | 0.785398 | 4 | 083 | 219.584 | -270 | 90.5595 | 270.559 | 6692.9 | 11330 | 11998.1 | 12101.3 | 11333.3
Poutre en Acier 1525452 | 1525452 | -0.785398 | 4 | 082 | 624.711 | -270 | 90.051 | 270.051 | 19041.2 | 32240 | 34134.2 | 34237.4 | 32243.1
Poutre en Acier 1525431 | 1525431 | 0.785398 | 2 | 079 | 346.864 | -270 | 90.0396 | 270.04 | 10572.4 | 17900 | 18952.6 | 19055.9 | 17902.6
Poutre en Acier 1525425 | 1525425 | 0.785398 | 2 | 078 | 373.038 | -272.5 | 89.9906 | 269.991 | 11370.2 | 19250 | 20382.8 | 20486 | 19253.5

# IfcBeam: 7,5x5 (40)
Type - Material: Aluminium mat
Description: Poutre en Acier; Group: ...de matériaux et couleurs = Aluminium mat; ...de profilés en acier = 7,5x5
__RECOGNIZE__ - TPLG: 214; TPLG_OD: 503; GENERATE: 1; Section_TypeForm: 0; AngleRotaz: 0; Section, Section_NumItems: 1; Section, Section_Item 0, Section_ID: 236; Section, Section_Item 0, Section_Desc: 7,5X5; Section, Section_Item 0, Section_Categ: 2; Section, Section_Item 0, Section_Tipo: 22; Section, Section_Item 0, Section_Base: 0.075; Section, Section_Item 0, Section_H: 0.05; Section, Section_Item 0, Section_DistPrfX: 0; Section, Section_Item 0, Section_DistPrfY: 0; Section, Section_Item 0, Section_DispInPianta: 0; Section, Section_Item 0, Section_TipoForma: 0; Section, Section_Item 0, Section_AngleRot: 0; Section, Section_Item 0, Section_BrcX: 0; Section, Section_Item 0, Section_BrcY: 0
IFC_PSET_PolygonOffset - polygonOffsetFactor: 2; polygonOffsetUnits: 2
IFC_Pset_Alignment - Alignment_Sez: 0; Alignment_Poly: -200; Alignment_NODO_CLC: 0; Alignment_C_FC_SUP: 0
IFC_Pset_Caractéristiques - Coupe: 7,5x5
IFC_Pset_Géométrie - Rotation: 0 deg
IFC_Pset_Système de Référence Altimétrique_SUPÉRIEUR - sous Niveau: <aucun>
IFC_Pset_Données Métré - Surface de la Section: 37.5 cm2; Base Section: 7.5 cm; Hauteur Section: 5 cm; Diamètre Section: 0 cm
IFC_Pset_Matériaux - Principal: Aluminium mat
Pset_BeamCommon - Reference: 7,5x5 (..\Profilés\Rectangulaire vide arêtes vives\)
BaseQuantities - CrossSectionArea: 11.0784 cm2
Name | In | __RECOGNIZE__, ID = IFC_Pset_Caractéristiques, ID | 0, DocType | 0, Tag | 0, Crc | 1, DocType | 1, Tag | 1, Crc | Alignment_Nodo | Alignment_TS | Numérotation | Numéro niveau | Titre niveau | IFC_Pset_Géométrie_P1 (POINT initial), Longueur (cm) = IFC_Pset_Géométrie_P2 (POINT final), Longueur (cm) = Span (cm) = NominalLength (cm) | IFC_Pset_Géométrie_P1 (POINT initial), Cote (cm) | IFC_Pset_Géométrie_P1 (POINT initial), Angle XY (deg) | IFC_Pset_Géométrie_P2 (POINT final), Cote (cm) = delta (P2) (cm) | IFC_Pset_Géométrie_P2 (POINT final), Angle XY (deg) | NIVEAU | delta (P1) (cm) | Surface (latérale) (cm2) | Volume (cm3) | Slope (deg) | OuterSurfaceArea (cm2) | TotalSurfaceArea (cm2) | GrossVolume (cm3) = NetVolume (cm3)
Poutre en Acier 954592 | Niveau 2 | 954592 | 2 | 0 | 913068333 | 7 | -10 | 1218297054 | 6 | 1 | 044 | 05 | Niveau 2 | 168.905 | -205 | 90.7649 | -180 | 270.765 | HAUT Niveau 2 (Mezzanine 49003) | -205 | 4222.6 | 1870 | 8.51173 | 7796.67 | 7818.82 | 1871.2
Poutre en Acier 954589 | Niveau 2 | 954589 | 2 | 0 | 913068333 | 7 | -10 | 1218297054 | 6 | 1 | 043 | 05 | Niveau 2 | 170.16 | -205 | 90.3915 | -180 | 270.391 | HAUT Niveau 2 (Mezzanine 49003) | -205 | 4254 | 1890 | 8.44849 | 7854.61 | 7876.76 | 1885.11
Poutre en Acier 954598 | Niveau 2 | 954598 | 2 | 0 | 913068333 | 7 | -10 | 1218297054 | 6 | 1 | 046 | 05 | Niveau 2 | 168.429 | -205 | 90.3543 | -180 | 270.354 | HAUT Niveau 2 (Mezzanine 49003) | -205 | 4210.7 | 1870 | 8.53599 | 7774.68 | 7796.83 | 1865.92
Poutre en Acier 954595 | Niveau 2 | 954595 | 2 | 0 | 913068333 | 7 | -10 | 1218297054 | 6 | 1 | 045 | 05 | Niveau 2 | 168.494 | -205 | 90.8665 | -180 | 270.867 | HAUT Niveau 2 (Mezzanine 49003) | -205 | 4212.4 | 1870 | 8.53266 | 7777.69 | 7799.84 | 1866.64
Poutre en Acier 954586 | Niveau 2 | 954586 | 2 | 0 | 913068333 | 7 | -10 | 1218297054 | 6 | 1 | 042 | 05 | Niveau 2 | 169.221 | -205 | 90.7395 | -180 | 270.739 | HAUT Niveau 2 (Mezzanine 49003) | -205 | 4230.5 | 1870 | 8.49574 | 7811.23 | 7833.39 | 1874.7
Poutre en Acier 954583 | Niveau 2 | 954583 | 2 | 0 | 913068333 | 7 | -10 | 1218297054 | 6 | 1 | 041 | 05 | Niveau 2 | 176.292 | -205 | 90.614 | -180 | 270.614 | HAUT Niveau 2 (Mezzanine 49003) | -205 | 4407.3 | 1950 | 8.15262 | 8137.62 | 8159.78 | 1953.03
Poutre en Acier 954619 | Niveau 2 | 954619 | 2 | 0 | 913068333 | 7 | -10 | 1218297054 | 0 | 1 | 053 | 05 | Niveau 2 | 168.608 | -205 | 89.5877 | -180 | 269.588 | HAUT Niveau 2 (Mezzanine 49003) | -205 | 4215.2 | 1870 | 8.52685 | 7782.95 | 7805.1 | 1867.91
Poutre en Acier 954616 | Niveau 2 | 954616 | 2 | 0 | 913068333 | 7 | -10 | 1218297054 | 6 | 1 | 052 | 05 | Niveau 2 | 168.684 | -205 | 89.7561 | -180 | 269.756 | HAUT Niveau 2 (Mezzanine 49003) | -205 | 4217.1 | 1870 | 8.52296 | 7786.47 | 7808.63 | 1868.75
Poutre en Acier 954625 | Niveau 2 | 954625 | 2 | 0 | 913068333 | 7 | -10 | 1218297054 | 6 | 1 | 055 | 05 | Niveau 2 | 169.585 | -205 | 89.6994 | -180 | 269.699 | HAUT Niveau 2 (Mezzanine 49003) | -205 | 4239.6 | 1880 | 8.47736 | 7828.05 | 7850.21 | 1878.73
Poutre en Acier 954622 | Niveau 2 | 954622 | 2 | 0 | 913068333 | 7 | -10 | 1218297054 | 2 | 1 | 054 | 05 | Niveau 2 | 169.357 | -205 | 89.7606 | -180 | 269.761 | HAUT Niveau 2 (Mezzanine 49003) | -205 | 4233.9 | 1880 | 8.48887 | 7817.51 | 7839.67 | 1876.2
Poutre en Acier 954613 | Niveau 2 | 954613 | 2 | 0 | 913068333 | 7 | -10 | 1218297054 | 6 | 1 | 051 | 05 | Niveau 2 | 169.08 | -205 | 89.7602 | -180 | 269.76 | HAUT Niveau 2 (Mezzanine 49003) | -205 | 4227 | 1870 | 8.50288 | 7804.73 | 7826.89 | 1873.13
Poutre en Acier 954604 | Niveau 2 | 954604 | 2 | 0 | 913068333 | 7 | -10 | 1218297054 | 6 | 1 | 048 | 05 | Niveau 2 | 168.93 | -205 | 89.8868 | -180 | 269.887 | HAUT Niveau 2 (Mezzanine 49003) | -205 | 4223.3 | 1870 | 8.51046 | 7797.83 | 7819.99 | 1871.48
Poutre en Acier 954601 | Niveau 2 | 954601 | 2 | 0 | 913068333 | 7 | -10 | 1218297054 | 6 | 1 | 047 | 05 | Niveau 2 | 167.833 | -205 | 90.1519 | -180 | 270.152 | HAUT Niveau 2 (Mezzanine 49003) | -205 | 4195.8 | 1860 | 8.56652 | 7747.17 | 7769.33 | 1859.32
Poutre en Acier 954610 | Niveau 2 | 954610 | 2 | 0 | 913068333 | 7 | -10 | 1218297054 | 6 | 1 | 050 | 05 | Niveau 2 | 169.038 | -205 | 90.5895 | -180 | 270.589 | HAUT Niveau 2 (Mezzanine 49003) | -205 | 4225.9 | 1870 | 8.50501 | 7802.78 | 7824.94 | 1872.67
Poutre en Acier 954607 | Niveau 2 | 954607 | 2 | 0 | 913068333 | 7 | -10 | 1218297054 | 6 | 1 | 049 | 05 | Niveau 2 | 168.27 | -205 | 89.6832 | -180 | 269.683 | HAUT Niveau 2 (Mezzanine 49003) | -205 | 4206.8 | 1860 | 8.54411 | 7767.35 | 7789.5 | 1864.16
Poutre en Acier 834606 | Couverture | 834606 | 7 | -10 | 1218297054 | 2 | 0 | 913068333 | 0 | 1 | 025 | 07 | Couverture | 188.097 | -30 | 89.2448 | -10 | 269.245 | Couverture (Couverture 2134) | -30 | 4702.4 | 2080 | 6.10368 | 8682.58 | 8704.74 | 2083.82
Poutre en Acier 834600 | Couverture | 834600 | 7 | -10 | 1218297054 | 2 | 0 | 913068333 | 0 | 1 | 024 | 07 | Couverture | 222.583 | -30 | 90.889 | -9.41592 | 270.889 | Couverture (Couverture 2134) | -30 | 5564.6 | 2470 | 5.30619 | 10274.4 | 10296.6 | 2465.86
Poutre en Acier 845024 | Couverture | 845024 | 7 | -10 | 1218297054 | 2 | 0 | 913068333 | 0 | 0 | 027 | 07 | Couverture | 238.895 | -9.9697 | 89.5161 | -35 | 269.516 | Couverture (Couverture 2134) | -9.9697 | 5972.4 | 2650 | -6.01423 | 11027.4 | 11049.5 | 2646.57
Poutre en Acier 834607 | Couverture | 834607 | 7 | -10 | 1218297054 | 2 | 0 | 913068333 | 0 | 0 | 026 | 07 | Couverture | 28.4835 | -33.2871 | 90.889 | -30.2369 | 270.889 | Couverture (Couverture 2134) | -33.2871 | 712.1 | 320 | 6.1475 | 1314.8 | 1336.95 | 315.551
Poutre en Acier 834597 | Couverture | 834597 | 7 | -10 | 1218297054 | 2 | 0 | 913068333 | 0 | 1 | 023 | 07 | Couverture | 221.265 | -30 | 90.889 | -9.55709 | 270.889 | Couverture (Couverture 2134) | -30 | 5531.6 | 2450 | 5.30118 | 10213.6 | 10235.7 | 2451.26
Poutre en Acier 834585 | Couverture | 834585 | 7 | -10 | 1218297054 | 2 | 0 | 913068333 | 2 | 1 | 020 | 07 | Couverture | 244.052 | -10 | 90.0188 | -40.1417 | 270.019 | Couverture (Couverture 2134) | -10 | 6101.3 | 2700 | -7.09446 | 11265.4 | 11287.6 | 2703.7
Poutre en Acier 834579 | Couverture | 834579 | 7 | -10 | 1218297054 | 2 | 0 | 913068333 | 0 | 1 | 019 | 07 | Couverture | 218.418 | -30 | 90.889 | -9.86202 | 270.889 | Couverture (Couverture 2134) | -30 | 5460.4 | 2420 | 5.29015 | 10082.2 | 10104.3 | 2419.72
Poutre en Acier 834594 | Couverture | 834594 | 7 | -10 | 1218297054 | 2 | 0 | 913068333 | 0 | 1 | 022 | 07 | Couverture | 220.828 | -30 | 90.889 | -9.60391 | 270.889 | Couverture (Couverture 2134) | -30 | 5520.7 | 2450 | 5.2995 | 10193.4 | 10215.6 | 2446.42
Poutre en Acier 834591 | Couverture | 834591 | 7 | -10 | 1218297054 | 2 | 0 | 913068333 | 0 | 1 | 021 | 07 | Couverture | 218.922 | -30 | 90.889 | -9.80807 | 270.889 | Couverture (Couverture 2134) | -30 | 5473 | 2430 | 5.29212 | 10105.4 | 10127.6 | 2425.3
Poutre en Acier 919693 | Couverture | 919693 | 7 | -10 | 1218297054 | 2 | 0 | 913068333 | 6 | 1 | 033 | 07 | Couverture | 289.706 | -51 | 102.214 | -94 | 282.214 | Couverture (Couverture 2134) | -51 | 7242.6 | 3210 | -8.53574 | 13372.8 | 13395 | 3209.48
Poutre en Acier 942522 | Couverture | 942522 | 2 | 0 | 913068333 | 7 | -10 | 1218297054 | 6 | 0 | 036 | 07 | Couverture | 196.346 | -98 | 3.03362 | -67 | 183.034 | Couverture (Couverture 2134) | -98 | 4908.7 | 2180 | 9.08412 | 9063.34 | 9085.49 | 2175.2
Poutre en Acier 942494 | Couverture | 942494 | 2 | 0 | 913068333 | 7 | -10 | 1218297054 | 0 | 0 | 035 | 07 | Couverture | 134.254 | -92 | 2.73478 | -70 | 182.735 | Couverture (Couverture 2134) | -92 | 3356.3 | 1490 | 9.43154 | 6197.14 | 6219.3 | 1487.31
Poutre en Acier 919690 | Couverture | 919690 | 7 | -10 | 1218297054 | 2 | 0 | 913068333 | 6 | 1 | 032 | 07 | Couverture | 225.976 | -60 | 102.236 | -93.43 | 282.236 | Couverture (Couverture 2134) | -60 | 5649.4 | 2500 | -8.50733 | 10431.1 | 10453.2 | 2503.45
Poutre en Acier 845025 | Couverture | 845025 | 7 | -10 | 1218297054 | 2 | 0 | 913068333 | 0 | 1 | 028 | 07 | Couverture | 223.331 | -30 | 90.889 | -9.33584 | 270.889 | Couverture (Couverture 2134) | -30 | 5583.3 | 2470 | 5.30901 | 10308.9 | 10331.1 | 2474.15
Poutre en Acier 919687 | Couverture | 919687 | 7 | -10 | 1218297054 | 2 | 0 | 913068333 | 6 | 1 | 031 | 07 | Couverture | 161.793 | -68 | 102.446 | -92 | 282.446 | Couverture (Couverture 2134) | -68 | 4044.8 | 1790 | -8.53059 | 7468.38 | 7490.53 | 1792.41
Poutre en Acier 919684 | Couverture | 919684 | 7 | -10 | 1218297054 | 2 | 0 | 913068333 | 6 | 1 | 030 | 07 | Couverture | 95.7641 | -76 | 102.564 | -92 | 282.564 | Couverture (Couverture 2134) | -76 | 2394.1 | 1060 | -9.61792 | 4420.47 | 4442.63 | 1060.91
Poutre en Acier 832337 | Couverture | 832337 | 7 | -10 | 1218297054 | 2 | 0 | 913068333 | 0 | 0 | 009 | 07 | Couverture | 243.291 | -10 | 91.1985 | -35 | 271.198 | Couverture (Couverture 2134) | -10 | 6082.3 | 2700 | -5.89798 | 11230.3 | 11252.5 | 2695.28
Poutre en Acier 832620 | Couverture | 832620 | 7 | -10 | 1218297054 | 2 | 0 | 913068333 | 0 | 0 | 011 | 07 | Couverture | 242.202 | -10 | 90.8972 | -35 | 270.897 | Couverture (Couverture 2134) | -10 | 6055.1 | 2680 | -5.9246 | 11180.1 | 11202.2 | 2683.21
Poutre en Acier 832617 | Couverture | 832617 | 7 | -10 | 1218297054 | 2 | 0 | 913068333 | 0 | 0 | 010 | 07 | Couverture | 242.719 | -10 | 90.8846 | -35 | 270.885 | Couverture (Couverture 2134) | -10 | 6068 | 2690 | -5.91194 | 11203.9 | 11226.1 | 2688.94
Poutre en Acier 832626 | Couverture | 832626 | 7 | -10 | 1218297054 | 2 | 0 | 913068333 | 0 | 0 | 013 | 07 | Couverture | 238.606 | -10 | 89.5161 | -35 | 269.516 | Couverture (Couverture 2134) | -10 | 5965.1 | 2640 | -6.01423 | 11014 | 11036.2 | 2643.37
Poutre en Acier 832623 | Couverture | 832623 | 7 | -10 | 1218297054 | 2 | 0 | 913068333 | 0 | 0 | 012 | 07 | Couverture | 239.361 | -10 | 89.4748 | -35 | 269.475 | Couverture (Couverture 2134) | -10 | 5984 | 2650 | -5.99518 | 11048.9 | 11071.1 | 2651.74
Poutre en Acier 942525 | Couverture | 942525 | 2 | 0 | 913068333 | 7 | -10 | 1218297054 | 6 | 1 | 037 | 07 | Couverture | 281.84 | -92 | 2.17526 | -56 | 182.175 | Couverture (Couverture 2134) | -92 | 7046 | 3120 | 7.33855 | 13009.7 | 13031.9 | 3122.34
Poutre en Acier 1510635 | Couverture | 1510635 | 7 | -10 | 1218297054 | 2 | 0 | 913068333 | 7 | 1 | 070 | 07 | Couverture | 187.993 | -245 | 118.925 | -272.115 | 298.925 | Couverture (Couverture 2134) | -245 | 4699.8 | 2080 | -8.29282 | 8677.75 | 8699.91 | 2082.66
Poutre en Acier 832333 | Couverture | 832333 | 7 | -10 | 1218297054 | 2 | 0 | 913068333 | 6 | 1 | 008 | 07 | Couverture | 390.315 | -7 | 179.867 | -7 | 359.867 | Couverture (Couverture 2134) | -7 | 1690.1 | 750 | 0 | 18016.9 | 18039.1 | 4324.07
Poutre en Acier 919681 | Couverture | 919681 | 7 | -10 | 1218297054 | 2 | 0 | 913068333 | 6 | 1 | 029 | 07 | Couverture | 519.681 | -33 | 140.868 | -80 | 320.868 | Couverture (Couverture 2134) | -70.6472 | 2585.4 | 1150 | -5.18892 | 23988.5 | 24010.7 | 5757.24

# IfcBeam: 80x120 (11)
In: Mezzanine
Type - Material: Eyong
Description: Poutre; Group: ...de matériaux et couleurs = Eyong; ...de sections pour tiges = 80x120
__RECOGNIZE__ - TPLG: 210; TPLG_OD: 501; GENERATE: 1; Section_TypeForm: 0; Section, Section_NumItems: 1; Section, Section_Item 0, Section_ID: 166; Section, Section_Item 0, Section_Desc: 80,00x120,00; Section, Section_Item 0, Section_Categ: 3; Section, Section_Item 0, Section_Tipo: 0; Section, Section_Item 0, Section_Base: 0.08; Section, Section_Item 0, Section_H: 0.12; Section, Section_Item 0, Section_DistPrfX: 0; Section, Section_Item 0, Section_DistPrfY: 0; Section, Section_Item 0, Section_DispInPianta: 0; Section, Section_Item 0, Section_TipoForma: 0; Section, Section_Item 0, Section_AngleRot: 0; Section, Section_Item 0, Section_BrcX: 0; Section, Section_Item 0, Section_BrcY: 0
CTLG_EXTERNAL_LINK - 0, DocType: 2; 0, Tag: 0; 0, Crc: 1459353355; 1, DocType: 6; 1, Tag: -10; 1, Crc: -1248983059
IFC_PSET_PolygonOffset - polygonOffsetFactor: 2; polygonOffsetUnits: 2
IFC_Pset_Alignment - Alignment_Sez: 0; Alignment_Nodo: 3; Alignment_NODO_CLC: 0; Alignment_C_FC_SUP: 0
IFC_Pset_Caractéristiques - Numéro niveau: 06; Titre niveau: Mezzanine; Coupe: 80x120
IFC_Pset_Système de Référence Altimétrique_SUPÉRIEUR - NIVEAU: HAUT Mezzanine (Couverture 2134); sous Niveau: <aucun>
IFC_Pset_Données Métré - Surface de la Section: 100 cm2; Base Section: 8 cm; Hauteur Section: 12 cm; Diamètre Section: 0 cm
IFC_Pset_Matériaux - Principal: Eyong
Pset_BeamCommon - Reference: 80x120 (..\Section rectangulaire\)
BaseQuantities - CrossSectionArea: 96 cm2
Name | __RECOGNIZE__, ID = IFC_Pset_Caractéristiques, ID | AngleRotaz = Rotation (deg) | Alignment_Poly | Alignment_TS | Numérotation | IFC_Pset_Géométrie_P1 (POINT initial), Longueur (cm) = IFC_Pset_Géométrie_P2 (POINT final), Longueur (cm) = Span (cm) = NominalLength (cm) | IFC_Pset_Géométrie_P1 (POINT initial), Cote (cm) | IFC_Pset_Géométrie_P1 (POINT initial), Angle XY (deg) | IFC_Pset_Géométrie_P2 (POINT final), Cote (cm) = delta (P2) (cm) | IFC_Pset_Géométrie_P2 (POINT final), Angle XY (deg) | delta (P1) (cm) | Surface (latérale) (cm2) | Volume (cm3) | Slope (deg) | OuterSurfaceArea (cm2) | TotalSurfaceArea (cm2) | GrossVolume (cm3) = NetVolume (cm3)
Poutre 1781085 | 1781085 | 0 | -1 | 1 | 075 | 107.484 | -40 | 88.6117 | -25.2778 | 268.612 | -40 | 4300 | 10000 | 7.87258 | 4299.38 | 4491.38 | 10318.5
Poutre 1781082 | 1781082 | 0 | -1 | 0 | 074 | 106.777 | -20 | 91.3619 | -41.5 | 271.362 | -20 | 4300 | 10000 | -11.6161 | 4271.09 | 4463.09 | 10250.6
Poutre 1785473 | 1785473 | 0 | -1 | 0 | 077 | 121.478 | 12.5227 | 135 | -40 | 315 | 12.5227 | 4900 | 10000 | -25.6176 | 4859.13 | 5051.13 | 11661.9
Poutre 1781088 | 1781088 | 0 | -1 | 1 | 076 | 124.992 | -40 | 45 | 14.3476 | 225 | -40 | 5000 | 10000 | 25.7731 | 4999.69 | 5191.69 | 11999.2
Poutre 1717291 | 1717291 | 0 | 0 | 1 | 057 | 45.2535 | -260 | 139.674 | -260 | 319.674 | -260 | 1800 | 0 | 0 | 1810.14 | 2002.14 | 4344.34
Poutre 1804513 | 1804513 | 1.49012e-08 | -1 | 1 | 080 | 294.518 | -53.8344 | 0.00000120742 | 168.426 | 180 | 115.6 | 11800 | 30000 | 48.9956 | 11780.7 | 11972.7 | 28273.7
Poutre 1792385 | 1792385 | 0 | -1 | 0 | 079 | 270.039 | 162.903 | 0.538159 | -37.5 | 180.538 | 115.689 | 10800 | 30000 | -47.9128 | 10801.6 | 10993.6 | 25923.8
Poutre 1881704 | 1881704 | 0 | -1 | 1 | 117 | 320 | 179.022 | 90.6626 | -70.0359 | 270.663 | 142.005 | 12800 | 30000 | -51.1059 | 12800 | 12992 | 30720
Poutre 1883045 | 1883045 | 0 | -1 | 1 | 118 | 284.807 | -75.7355 | 90 | 145 | 270 | -75.7355 | 11400 | 30000 | 50.8082 | 11392.3 | 11584.3 | 27341.5
Poutre 1873937 | 1873937 | 0 | -1 | 1 | 114 | 39.0354 | 142.022 | 90 | 172.276 | 270 | 142.022 | 1600 | 0 | 50.8082 | 1561.42 | 1753.42 | 3747.4
Poutre 1900126 | 1900126 | 0.785398 | -1 | 1 | 126 | 521.136 | -65 | 90.1351 | -65 | 270.135 | -65 | 20800 | 50000 | 0 | 20845.5 | 21037.5 | 50029.1

# IfcBeam: 80x80 (19)
In: Mezzanine
Type - Material: Eyong
Description: Poutre; Group: ...de matériaux et couleurs = Eyong; ...de sections pour tiges = 80x80
__RECOGNIZE__ - TPLG: 210; TPLG_OD: 501; GENERATE: 1; Section_TypeForm: 0; Section, Section_NumItems: 1; Section, Section_Item 0, Section_ID: 176; Section, Section_Item 0, Section_Desc: 80.00x80.00; Section, Section_Item 0, Section_Categ: 3; Section, Section_Item 0, Section_Tipo: 0; Section, Section_Item 0, Section_Base: 0.08; Section, Section_Item 0, Section_H: 0.08; Section, Section_Item 0, Section_DistPrfX: 0; Section, Section_Item 0, Section_DistPrfY: 0; Section, Section_Item 0, Section_DispInPianta: 0; Section, Section_Item 0, Section_TipoForma: 0; Section, Section_Item 0, Section_AngleRot: 0; Section, Section_Item 0, Section_BrcX: 0; Section, Section_Item 0, Section_BrcY: 0
CTLG_EXTERNAL_LINK - 0, DocType: 2; 0, Tag: 0; 0, Crc: 1459353355; 1, DocType: 6; 1, Tag: -10; 1, Crc: -1530591034
IFC_PSET_PolygonOffset - polygonOffsetFactor: 2; polygonOffsetUnits: 2
IFC_Pset_Alignment - Alignment_Sez: 0; Alignment_NODO_CLC: 0; Alignment_C_FC_SUP: 0
IFC_Pset_Caractéristiques - Numéro niveau: 06; Titre niveau: Mezzanine; Coupe: 80x80
IFC_Pset_Système de Référence Altimétrique_SUPÉRIEUR - NIVEAU: HAUT Mezzanine (Couverture 2134); sous Niveau: <aucun>
IFC_Pset_Données Métré - Surface de la Section: 100 cm2; Base Section: 8 cm; Hauteur Section: 8 cm; Diamètre Section: 0 cm
IFC_Pset_Matériaux - Principal: Eyong
Pset_BeamCommon - Reference: 80x80 (..\Section rectangulaire\)
BaseQuantities - CrossSectionArea: 64 cm2
Name | __RECOGNIZE__, ID = IFC_Pset_Caractéristiques, ID | AngleRotaz = Rotation (deg) | Alignment_Poly | Alignment_Nodo | Alignment_TS | Numérotation | IFC_Pset_Géométrie_P1 (POINT initial), Longueur (cm) = IFC_Pset_Géométrie_P2 (POINT final), Longueur (cm) = Span (cm) = NominalLength (cm) | IFC_Pset_Géométrie_P1 (POINT initial), Cote (cm) = delta (P1) (cm) | IFC_Pset_Géométrie_P1 (POINT initial), Angle XY (deg) | IFC_Pset_Géométrie_P2 (POINT final), Cote (cm) = delta (P2) (cm) | IFC_Pset_Géométrie_P2 (POINT final), Angle XY (deg) | Surface (latérale) (cm2) | Volume (cm3) | Slope (deg) | OuterSurfaceArea (cm2) | TotalSurfaceArea (cm2) | GrossVolume (cm3) = NetVolume (cm3)
Poutre 1805044 | 1805044 | 0 | -1 | 3 | 1 | 083 | 107.563 | -50 | 90 | -22 | 270 | 3400 | 10000 | 15.0886 | 3442.01 | 3570.01 | 6884.02
Poutre 1805055 | 1805055 | 0 | -1 | 3 | 1 | 084 | 135 | -56.258 | 137.414 | 7.03225 | 317.414 | 4300 | 10000 | 27.9575 | 4320 | 4448 | 8640
Poutre 1819922 | 1819922 | 0 | 0 | 3 | 1 | 097 | 200.674 | -200 | 178.952 | -84.4303 | 358.952 | 6400 | 10000 | 35.1631 | 6421.58 | 6549.58 | 12843.2
Poutre 1791735 | 1791735 | 0 | -1 | 3 | 0 | 078 | 109.979 | -24.8645 | 90.9815 | -47 | 270.981 | 3500 | 10000 | -11.6112 | 3519.33 | 3647.33 | 7038.66
Poutre 1875076 | 1875076 | 0 | -1 | 3 | 0 | 115 | 114.948 | -35.5949 | 1.75898 | -70 | 181.759 | 3700 | 10000 | -17.4161 | 3678.34 | 3806.34 | 7356.69
Poutre 1879254 | 1879254 | 0 | -1 | 3 | 1 | 116 | 110.22 | 0 | 135.59 | 0 | 315.59 | 3500 | 10000 | 0 | 3527.03 | 3655.03 | 7054.05
Poutre 1820269 | 1820269 | 0 | 0 | 3 | 1 | 103 | 200 | -200 | 178.952 | -72.9167 | 358.952 | 6400 | 10000 | 39.4509 | 6400 | 6528 | 12800
Poutre 1820286 | 1820286 | 0 | 0 | 0 | 1 | 105 | 192.13 | -100 | 90.2176 | -200 | 270.218 | 6100 | 10000 | -31.3645 | 6148.16 | 6276.16 | 12296.3
Poutre 1820283 | 1820283 | 0 | 0 | 0 | 0 | 104 | 240 | -61.3203 | 42.8486 | -199.98 | 222.849 | 7700 | 20000 | -35.2924 | 7680 | 7808 | 15360
Poutre 1819943 | 1819943 | 0 | 0 | 3 | 1 | 099 | 208.663 | -198 | 88.9521 | -90.9912 | 268.952 | 6700 | 10000 | 30.8525 | 6677.23 | 6805.23 | 13354.5
Poutre 1819940 | 1819940 | 0 | 0 | 3 | 1 | 098 | 194.779 | -200 | 135.328 | -95 | 315.328 | 6200 | 10000 | 32.6205 | 6232.93 | 6360.93 | 12465.9
Poutre 1819956 | 1819956 | 0 | 0 | 3 | 1 | 101 | 251.397 | -200 | 0.925182 | -69.1527 | 180.925 | 8000 | 20000 | 31.3645 | 8044.7 | 8172.7 | 16089.4
Poutre 1819950 | 1819950 | 0 | 0 | 3 | 1 | 100 | 238.938 | -198 | 43.9521 | -75.4655 | 223.952 | 7600 | 20000 | 30.8525 | 7646.01 | 7774.01 | 15292
Poutre 1872902 | 1872902 | 0 | -1 | 3 | 0 | 111 | 172.674 | 12.4607 | 136.95 | -65 | 316.95 | 5500 | 10000 | -26.6535 | 5525.58 | 5653.58 | 11051.2
Poutre 1872884 | 1872884 | 0 | -1 | 3 | 1 | 110 | 119.813 | -65 | 2.55324 | -38.3784 | 182.553 | 3800 | 10000 | 12.8379 | 3834 | 3962 | 7668
Poutre 1873925 | 1873925 | -2.10734e-08 | -1 | 3 | 0 | 113 | 118.267 | -36.6889 | 0.00000147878 | -62 | 180 | 3800 | 10000 | -12.3579 | 3784.53 | 3912.53 | 7569.07
Poutre 1872920 | 1872920 | 0 | -1 | 3 | 0 | 112 | 163.217 | 9.82726 | 45 | -60 | 225 | 5200 | 10000 | -25.3292 | 5222.95 | 5350.95 | 10445.9
Poutre 1820292 | 1820292 | 0 | 0 | 0 | 1 | 107 | 192.13 | -100 | 178.952 | -200 | 358.952 | 6100 | 10000 | -31.3645 | 6148.16 | 6276.16 | 12296.3
Poutre 1820289 | 1820289 | 0 | 0 | 0 | 1 | 106 | 200.674 | -84.4303 | 136.415 | -200 | 316.415 | 6400 | 10000 | -35.1631 | 6421.58 | 6549.58 | 12843.2

# IfcBeam: RND 35 (63)
Type - Material: Aluminium mat
Description: Poutre en Acier; Group: ...de matériaux et couleurs = Aluminium mat; ...de profilés en acier = RND 35
__RECOGNIZE__ - TPLG: 214; TPLG_OD: 503; GENERATE: 1; Section_TypeForm: 0; AngleRotaz: 0; Section, Section_NumItems: 1; Section, Section_Item 0, Section_ID: 212; Section, Section_Item 0, Section_Desc: RND 35; Section, Section_Item 0, Section_Categ: 2; Section, Section_Item 0, Section_Tipo: 23; Section, Section_Item 0, Section_Base: 0.035; Section, Section_Item 0, Section_H: 0.035; Section, Section_Item 0, Section_DistPrfX: 0; Section, Section_Item 0, Section_DistPrfY: 0; Section, Section_Item 0, Section_DispInPianta: 0; Section, Section_Item 0, Section_TipoForma: 0; Section, Section_Item 0, Section_AngleRot: 0; Section, Section_Item 0, Section_BrcX: 0; Section, Section_Item 0, Section_BrcY: 0
IFC_PSET_PolygonOffset - polygonOffsetFactor: 2; polygonOffsetUnits: 2
IFC_Pset_Alignment - Alignment_Sez: 0; Alignment_NODO_CLC: 0; Alignment_C_FC_SUP: 0
IFC_Pset_Caractéristiques - Coupe: RND 35
IFC_Pset_Géométrie - Rotation: 0 deg
IFC_Pset_Système de Référence Altimétrique_SUPÉRIEUR - sous Niveau: <aucun>
IFC_Pset_Données Métré - Surface de la Section: 12.3 cm2; Base Section: 3.5 cm; Hauteur Section: 3.5 cm; Diamètre Section: 3.5 cm
IFC_Pset_Matériaux - Principal: Aluminium mat
Pset_BeamCommon - Reference: RND 35 (..\Profilés\Rond\)
BaseQuantities - CrossSectionArea: 9.60892 cm2
Name | In | __RECOGNIZE__, ID = IFC_Pset_Caractéristiques, ID | 0, DocType | 0, Tag | 0, Crc | 1, DocType | 1, Tag | 1, Crc | Alignment_Poly | Alignment_Nodo | Alignment_TS | Numérotation | Numéro niveau | Titre niveau | IFC_Pset_Géométrie_P1 (POINT initial), Longueur (cm) = IFC_Pset_Géométrie_P2 (POINT final), Longueur (cm) = Span (cm) = NominalLength (cm) | IFC_Pset_Géométrie_P1 (POINT initial), Cote (cm) = delta (P1) (cm) | IFC_Pset_Géométrie_P1 (POINT initial), Angle XY (deg) | IFC_Pset_Géométrie_P2 (POINT final), Cote (cm) = delta (P2) (cm) | IFC_Pset_Géométrie_P2 (POINT final), Angle XY (deg) | NIVEAU | Surface (latérale) (cm2) | Volume (cm3) | Slope (deg) | OuterSurfaceArea (cm2) | TotalSurfaceArea (cm2) | GrossVolume (cm3) = NetVolume (cm3)
Poutre en Acier 1550562 | Rez-de-chaussée | 1550562 | 2 | 0 | 913068333 | 7 | -10 | 2097014839 | -1 | -10 | 0 | 110 | 03 | Rez-de-chaussée | 129.762 | -377 | 90 | -377 | 270 | HAUT Rez-de-chaussée (Niveau 1 2343) | 1426.8 | 1250 | 0 | 1426.81 | 1446.02 | 1246.87
Poutre en Acier 1550687 | Rez-de-chaussée | 1550687 | 2 | 0 | 913068333 | 7 | -10 | 2097014839 | -1 | -10 | 1 | 111 | 03 | Rez-de-chaussée | 129.762 | -398 | 89.9714 | -398 | 269.971 | HAUT Rez-de-chaussée (Niveau 1 2343) | 1426.8 | 1250 | 0 | 1426.8 | 1446.02 | 1246.87
Poutre en Acier 1660656 | Rez-de-chaussée | 1660656 | 2 | 0 | 913068333 | 7 | -10 | 2097014839 | -200 | 4 | 1 | 136 | 03 | Rez-de-chaussée | 130.26 | -418 | 135.126 | -418 | 315.126 | HAUT Rez-de-chaussée (Niveau 1 2343) | 1432.3 | 1250 | 1.41245e-30 | 1432.28 | 1451.5 | 1251.65
Poutre en Acier 1660529 | Rez-de-chaussée | 1660529 | 2 | 0 | 913068333 | 7 | -10 | 2097014839 | -200 | 4 | 0 | 135 | 03 | Rez-de-chaussée | 130.26 | -400 | 135.126 | -400 | 315.126 | HAUT Rez-de-chaussée (Niveau 1 2343) | 1432.3 | 1250 | -1.41245e-30 | 1432.29 | 1451.5 | 1251.66
Poutre en Acier 1661839 | Rez-de-chaussée | 1661839 | 2 | 0 | 913068333 | 7 | -10 | 2097014839 | -200 | 0 | 1 | 138 | 03 | Rez-de-chaussée | 130.308 | -414.5 | 44.8748 | -414.5 | 224.875 | HAUT Rez-de-chaussée (Niveau 1 2343) | 1432.8 | 1250 | 0 | 1432.81 | 1452.03 | 1252.12
Poutre en Acier 1661667 | Rez-de-chaussée | 1661667 | 2 | 0 | 913068333 | 7 | -10 | 2097014839 | -200 | 0 | 0 | 137 | 03 | Rez-de-chaussée | 130.308 | -377 | 44.8748 | -377 | 224.875 | HAUT Rez-de-chaussée (Niveau 1 2343) | 1432.8 | 1250 | 0 | 1432.81 | 1452.03 | 1252.12
Poutre en Acier 1660463 | Rez-de-chaussée | 1660463 | 2 | 0 | 913068333 | 7 | -10 | 2097014839 | -200 | 4 | 0 | 134 | 03 | Rez-de-chaussée | 130.26 | -383 | 135.126 | -383 | 315.126 | HAUT Rez-de-chaussée (Niveau 1 2343) | 1432.3 | 1250 | 0 | 1432.28 | 1451.5 | 1251.65
Poutre en Acier 1659932 | Rez-de-chaussée | 1659932 | 2 | 0 | 913068333 | 7 | -10 | 2097014839 | -200 | 4 | 0 | 131 | 03 | Rez-de-chaussée | 130.46 | -382.438 | 89.6897 | -382.438 | 269.69 | HAUT Rez-de-chaussée (Niveau 1 2343) | 1434.5 | 1250 | 0 | 1434.49 | 1453.7 | 1253.58
Poutre en Acier 1659367 | Rez-de-chaussée | 1659367 | 2 | 0 | 913068333 | 7 | -10 | 2097014839 | -200 | 0 | 0 | 130 | 03 | Rez-de-chaussée | 130.023 | -417.287 | 179.953 | -417.287 | 359.953 | HAUT Rez-de-chaussée (Niveau 1 2343) | 1429.7 | 1250 | 0 | 1429.67 | 1448.89 | 1249.38
Poutre en Acier 1660054 | Rez-de-chaussée | 1660054 | 2 | 0 | 913068333 | 7 | -10 | 2097014839 | -200 | 6 | 0 | 133 | 03 | Rez-de-chaussée | 130.46 | -415.026 | 89.6897 | -415.026 | 269.69 | HAUT Rez-de-chaussée (Niveau 1 2343) | 1434.5 | 1250 | 0 | 1434.49 | 1453.7 | 1253.58
Poutre en Acier 1659993 | Rez-de-chaussée | 1659993 | 2 | 0 | 913068333 | 7 | -10 | 2097014839 | -200 | 4 | 1 | 132 | 03 | Rez-de-chaussée | 130.46 | -401.685 | 89.6897 | -401.685 | 269.69 | HAUT Rez-de-chaussée (Niveau 1 2343) | 1434.5 | 1250 | 0 | 1434.49 | 1453.7 | 1253.58
Poutre en Acier 1664203 | Rez-de-chaussée | 1664203 | 2 | 0 | 913068333 | 7 | -10 | 2097014839 | -200 | 0 | 0 | 145 | 03 | Rez-de-chaussée | 129.923 | -417.029 | 0.106206 | -417.029 | 180.106 | HAUT Rez-de-chaussée (Niveau 1 2343) | 1428.6 | 1250 | 0 | 1428.58 | 1447.79 | 1248.42
Poutre en Acier 1664082 | Rez-de-chaussée | 1664082 | 2 | 0 | 913068333 | 7 | -10 | 2097014839 | -200 | 0 | 1 | 144 | 03 | Rez-de-chaussée | 129.923 | -398.567 | 0.106206 | -398.567 | 180.106 | HAUT Rez-de-chaussée (Niveau 1 2343) | 1428.6 | 1250 | 0 | 1428.58 | 1447.79 | 1248.42
Poutre en Acier 1664019 | Rez-de-chaussée | 1664019 | 2 | 0 | 913068333 | 7 | -10 | 2097014839 | -200 | 0 | 0 | 143 | 03 | Rez-de-chaussée | 129.923 | -380.769 | 0.106206 | -380.769 | 180.106 | HAUT Rez-de-chaussée (Niveau 1 2343) | 1428.6 | 1250 | 0 | 1428.58 | 1447.79 | 1248.42
Poutre en Acier 1663350 | Rez-de-chaussée | 1663350 | 2 | 0 | 913068333 | 7 | -10 | 2097014839 | -200 | 0 | 0 | 140 | 03 | Rez-de-chaussée | 130.421 | -379 | 0.106161 | -379 | 180.106 | HAUT Rez-de-chaussée (Niveau 1 2343) | 1434.1 | 1250 | 0 | 1434.05 | 1453.27 | 1253.2
Poutre en Acier 1661907 | Rez-de-chaussée | 1661907 | 2 | 0 | 913068333 | 7 | -10 | 2097014839 | -200 | 2 | 1 | 139 | 03 | Rez-de-chaussée | 130.308 | -400 | 44.8748 | -400 | 224.875 | HAUT Rez-de-chaussée (Niveau 1 2343) | 1432.8 | 1250 | 0 | 1432.81 | 1452.03 | 1252.12
Poutre en Acier 1663476 | Rez-de-chaussée | 1663476 | 2 | 0 | 913068333 | 7 | -10 | 2097014839 | -200 | 0 | 0 | 142 | 03 | Rez-de-chaussée | 130.421 | -416.678 | 0.106207 | -416.678 | 180.106 | HAUT Rez-de-chaussée (Niveau 1 2343) | 1434.1 | 1250 | 0 | 1434.05 | 1453.27 | 1253.2
Poutre en Acier 1663413 | Rez-de-chaussée | 1663413 | 2 | 0 | 913068333 | 7 | -10 | 2097014839 | -200 | 0 | 0 | 141 | 03 | Rez-de-chaussée | 130.422 | -397.795 | 0.106161 | -397.795 | 180.106 | HAUT Rez-de-chaussée (Niveau 1 2343) | 1434.1 | 1250 | 0 | 1434.07 | 1453.28 | 1253.22
Poutre en Acier 1553046 | Rez-de-chaussée | 1553046 | 2 | 0 | 913068333 | 7 | -10 | 2097014839 | -200 | 0 | 1 | 118 | 03 | Rez-de-chaussée | 129.828 | -413.163 | 179.855 | -413.163 | 359.855 | HAUT Rez-de-chaussée (Niveau 1 2343) | 1427.5 | 1250 | 0 | 1427.54 | 1446.76 | 1247.51
Poutre en Acier 1552977 | Rez-de-chaussée | 1552977 | 2 | 0 | 913068333 | 7 | -10 | 2097014839 | -200 | 0 | 1 | 117 | 03 | Rez-de-chaussée | 129.828 | -394.241 | 179.855 | -394.241 | 359.855 | HAUT Rez-de-chaussée (Niveau 1 2343) | 1427.5 | 1250 | 0 | 1427.54 | 1446.76 | 1247.51
Poutre en Acier 1656398 | Rez-de-chaussée | 1656398 | 2 | 0 | 913068333 | 7 | -10 | 2097014839 | -200 | 0 | 0 | 120 | 03 | Rez-de-chaussée | 129.534 | -395 | 179.869 | -395 | 359.869 | HAUT Rez-de-chaussée (Niveau 1 2343) | 1424.3 | 1240 | 0 | 1424.3 | 1443.52 | 1244.68
Poutre en Acier 1656274 | Rez-de-chaussée | 1656274 | 2 | 0 | 913068333 | 7 | -10 | 2097014839 | -200 | 0 | 1 | 119 | 03 | Rez-de-chaussée | 129.534 | -378 | 179.869 | -378 | 359.869 | HAUT Rez-de-chaussée (Niveau 1 2343) | 1424.3 | 1240 | 0 | 1424.3 | 1443.52 | 1244.68
Poutre en Acier 1552908 | Rez-de-chaussée | 1552908 | 2 | 0 | 913068333 | 7 | -10 | 2097014839 | -200 | 0 | 1 | 116 | 03 | Rez-de-chaussée | 129.828 | -378.715 | 179.855 | -378.715 | 359.855 | HAUT Rez-de-chaussée (Niveau 1 2343) | 1427.5 | 1250 | 0 | 1427.54 | 1446.76 | 1247.51
Poutre en Acier 1551991 | Rez-de-chaussée | 1551991 | 2 | 0 | 913068333 | 7 | -10 | 2097014839 | -200 | 1 | 1 | 113 | 03 | Rez-de-chaussée | 130.071 | -377 | 179.855 | -377 | 359.855 | HAUT Rez-de-chaussée (Niveau 1 2343) | 1430.2 | 1250 | 5.51738e-33 | 1430.21 | 1449.42 | 1249.84
Poutre en Acier 1550751 | Rez-de-chaussée | 1550751 | 2 | 0 | 913068333 | 7 | -10 | 2097014839 | -1 | -10 | 1 | 112 | 03 | Rez-de-chaussée | 129.762 | -418 | 90 | -418 | 270 | HAUT Rez-de-chaussée (Niveau 1 2343) | 1426.8 | 1250 | 0 | 1426.81 | 1446.02 | 1246.87
Poutre en Acier 1552575 | Rez-de-chaussée | 1552575 | 2 | 0 | 913068333 | 7 | -10 | 2097014839 | -200 | 1 | 1 | 115 | 03 | Rez-de-chaussée | 130.071 | -414.594 | 179.855 | -414.594 | 359.855 | HAUT Rez-de-chaussée (Niveau 1 2343) | 1430.2 | 1250 | 0 | 1430.21 | 1449.42 | 1249.84
Poutre en Acier 1552506 | Rez-de-chaussée | 1552506 | 2 | 0 | 913068333 | 7 | -10 | 2097014839 | -200 | 1 | 1 | 114 | 03 | Rez-de-chaussée | 130.071 | -396.157 | 179.855 | -396.157 | 359.855 | HAUT Rez-de-chaussée (Niveau 1 2343) | 1430.2 | 1250 | 0 | 1430.21 | 1449.42 | 1249.84
Poutre en Acier 1658545 | Rez-de-chaussée | 1658545 | 2 | 0 | 913068333 | 7 | -10 | 2097014839 | -200 | 0 | 0 | 127 | 03 | Rez-de-chaussée | 130.302 | -415.818 | 179.842 | -415.818 | 359.842 | HAUT Rez-de-chaussée (Niveau 1 2343) | 1432.7 | 1250 | 0 | 1432.75 | 1451.96 | 1252.06
Poutre en Acier 1658480 | Rez-de-chaussée | 1658480 | 2 | 0 | 913068333 | 7 | -10 | 2097014839 | -200 | 2 | 0 | 126 | 03 | Rez-de-chaussée | 130.302 | -400.881 | 179.842 | -400.881 | 359.842 | HAUT Rez-de-chaussée (Niveau 1 2343) | 1432.7 | 1250 | 0 | 1432.75 | 1451.96 | 1252.06
Poutre en Acier 1659302 | Rez-de-chaussée | 1659302 | 2 | 0 | 913068333 | 7 | -10 | 2097014839 | -200 | 0 | 0 | 129 | 03 | Rez-de-chaussée | 130.023 | -400.209 | 179.953 | -400.209 | 359.953 | HAUT Rez-de-chaussée (Niveau 1 2343) | 1429.7 | 1250 | 0 | 1429.67 | 1448.89 | 1249.38
Poutre en Acier 1659177 | Rez-de-chaussée | 1659177 | 2 | 0 | 913068333 | 7 | -10 | 2097014839 | -200 | 0 | 1 | 128 | 03 | Rez-de-chaussée | 130.023 | -381.189 | 179.953 | -381.189 | 359.953 | HAUT Rez-de-chaussée (Niveau 1 2343) | 1429.7 | 1250 | 0 | 1429.67 | 1448.89 | 1249.38
Poutre en Acier 1658354 | Rez-de-chaussée | 1658354 | 2 | 0 | 913068333 | 7 | -10 | 2097014839 | -200 | 2 | 1 | 125 | 03 | Rez-de-chaussée | 130.302 | -381.959 | 179.842 | -381.959 | 359.842 | HAUT Rez-de-chaussée (Niveau 1 2343) | 1432.7 | 1250 | 0 | 1432.75 | 1451.96 | 1252.06
Poutre en Acier 1657460 | Rez-de-chaussée | 1657460 | 2 | 0 | 913068333 | 7 | -10 | 2097014839 | -200 | 2 | 0 | 122 | 03 | Rez-de-chaussée | 201.818 | -384 | 179.869 | -384 | 359.869 | HAUT Rez-de-chaussée (Niveau 1 2343) | 2219.1 | 1940 | 0 | 2219.11 | 2238.33 | 1939.26
Poutre en Acier 1656522 | Rez-de-chaussée | 1656522 | 2 | 0 | 913068333 | 7 | -10 | 2097014839 | -200 | 0 | 1 | 121 | 03 | Rez-de-chaussée | 129.534 | -414 | 179.869 | -414 | 359.869 | HAUT Rez-de-chaussée (Niveau 1 2343) | 1424.3 | 1240 | 0 | 1424.3 | 1443.52 | 1244.68
Poutre en Acier 1657596 | Rez-de-chaussée | 1657596 | 2 | 0 | 913068333 | 7 | -10 | 2097014839 | -200 | 1 | 0 | 124 | 03 | Rez-de-chaussée | 201.818 | -417.773 | 179.87 | -417.773 | 359.87 | HAUT Rez-de-chaussée (Niveau 1 2343) | 2219.1 | 1940 | 0 | 2219.11 | 2238.33 | 1939.26
Poutre en Acier 1657528 | Rez-de-chaussée | 1657528 | 2 | 0 | 913068333 | 7 | -10 | 2097014839 | -200 | 2 | 0 | 123 | 03 | Rez-de-chaussée | 201.818 | -402.541 | 179.869 | -402.541 | 359.869 | HAUT Rez-de-chaussée (Niveau 1 2343) | 2219.1 | 1940 | 0 | 2219.11 | 2238.33 | 1939.26
Poutre en Acier 1549929 | Niveau 1 | 1549929 | 2 | 0 | 913068333 | 7 | -10 | 2097014839 | -200 | 0 | 1 | 099 | 04 | Niveau 1 | 110.59 | -276.347 | 179.841 | -276.347 | 359.841 | HAUT Niveau 1 (Niveau 2 13545) | 1216 | 1060 | 0 | 1216 | 1235.22 | 1062.65
Poutre en Acier 1549896 | Niveau 1 | 1549896 | 2 | 0 | 913068333 | 7 | -10 | 2097014839 | -200 | 0 | 1 | 098 | 04 | Niveau 1 | 109.889 | -273 | 89.8082 | -273 | 269.808 | HAUT Niveau 1 (Niveau 2 13545) | 1208.3 | 1060 | -5.51738e-33 | 1208.29 | 1227.51 | 1055.92
Poutre en Acier 1550090 | Niveau 1 | 1550090 | 2 | 0 | 913068333 | 7 | -10 | 2097014839 | -200 | 0 | 0 | 101 | 04 | Niveau 1 | 69.6727 | -274 | 179.869 | -274 | 359.869 | HAUT Niveau 1 (Niveau 2 13545) | 766.1 | 670 | 0 | 766.091 | 785.309 | 669.479
Poutre en Acier 1550015 | Niveau 1 | 1550015 | 2 | 0 | 913068333 | 7 | -10 | 2097014839 | -200 | 0 | 1 | 100 | 04 | Niveau 1 | 109.719 | -275.32 | 179.841 | -275.32 | 359.841 | HAUT Niveau 1 (Niveau 2 13545) | 1206.4 | 1050 | 0 | 1206.42 | 1225.64 | 1054.28
Poutre en Acier 1550466 | Niveau 1 | 1550466 | 2 | 0 | 913068333 | 7 | -10 | 2097014839 | -200 | 0 | 0 | 108 | 04 | Niveau 1 | 109.985 | -271.004 | 0.119595 | -271.004 | 180.12 | HAUT Niveau 1 (Niveau 2 13545) | 1209.3 | 1060 | 0 | 1209.35 | 1228.56 | 1056.83
Poutre en Acier 1550348 | Niveau 1 | 1550348 | 2 | 0 | 913068333 | 7 | -10 | 2097014839 | -200 | 0 | 1 | 107 | 04 | Niveau 1 | 110.063 | -275.079 | 44.8748 | -275.079 | 224.875 | HAUT Niveau 1 (Niveau 2 13545) | 1210.2 | 1060 | -1.41245e-30 | 1210.21 | 1229.42 | 1057.59
Poutre en Acier 1550499 | Niveau 1 | 1550499 | 2 | 0 | 913068333 | 7 | -10 | 2097014839 | -200 | 0 | 1 | 109 | 04 | Niveau 1 | 109.985 | -271.026 | 0.119595 | -271.026 | 180.12 | HAUT Niveau 1 (Niveau 2 13545) | 1209.3 | 1060 | 0 | 1209.35 | 1228.56 | 1056.83
Poutre en Acier 1550296 | Niveau 1 | 1550296 | 2 | 0 | 913068333 | 7 | -10 | 2097014839 | -200 | 6 | 0 | 106 | 04 | Niveau 1 | 109.862 | -275.461 | 135.126 | -275.461 | 315.126 | HAUT Niveau 1 (Niveau 2 13545) | 1208 | 1060 | 0 | 1208 | 1227.22 | 1055.66
Poutre en Acier 1550203 | Niveau 1 | 1550203 | 2 | 0 | 913068333 | 7 | -10 | 2097014839 | -200 | 0 | 1 | 103 | 04 | Niveau 1 | 109.629 | -275.152 | 179.629 | -277.191 | 359.629 | HAUT Niveau 1 (Niveau 2 13545) | 1205.4 | 1050 | -1.06595 | 1205.43 | 1224.65 | 1053.41
Poutre en Acier 1550172 | Niveau 1 | 1550172 | 2 | 0 | 913068333 | 7 | -10 | 2097014839 | -200 | 0 | 0 | 102 | 04 | Niveau 1 | 69.6974 | -272.25 | 179.869 | -272.25 | 359.869 | HAUT Niveau 1 (Niveau 2 13545) | 766.4 | 670 | 0 | 766.363 | 785.581 | 669.717
Poutre en Acier 1550265 | Niveau 1 | 1550265 | 2 | 0 | 913068333 | 7 | -10 | 2097014839 | -200 | 6 | 1 | 105 | 04 | Niveau 1 | 109.644 | -275.548 | 89.6897 | -275.548 | 269.69 | HAUT Niveau 1 (Niveau 2 13545) | 1205.6 | 1050 | 0 | 1205.6 | 1224.81 | 1053.56
Poutre en Acier 1550234 | Niveau 1 | 1550234 | 2 | 0 | 913068333 | 7 | -10 | 2097014839 | -200 | 0 | 0 | 104 | 04 | Niveau 1 | 110.087 | -274.34 | 179.953 | -274.34 | 359.953 | HAUT Niveau 1 (Niveau 2 13545) | 1210.5 | 1060 | 0 | 1210.47 | 1229.69 | 1057.82
Poutre en Acier 1549782 | Niveau 2 | 1549782 | 2 | 0 | 913068333 | 7 | -10 | 2097014839 | -200 | 0 | 0 | 097 | 05 | Niveau 2 | 100.871 | -134.625 | 0.119595 | -134.625 | 180.12 | HAUT Niveau 2 (Mezzanine 49003) | 1109.1 | 970 | 0 | 1109.13 | 1128.35 | 969.258
Poutre en Acier 1549147 | Niveau 2 | 1549147 | 2 | 0 | 913068333 | 7 | -10 | 2097014839 | -200 | 6 | 0 | 094 | 05 | Niveau 2 | 101.552 | -132.449 | 135.126 | -132.449 | 315.126 | HAUT Niveau 2 (Mezzanine 49003) | 1116.6 | 980 | 0 | 1116.63 | 1135.85 | 975.809
Poutre en Acier 1549063 | Niveau 2 | 1549063 | 2 | 0 | 913068333 | 7 | -10 | 2097014839 | -200 | 6 | 0 | 093 | 05 | Niveau 2 | 99.6884 | -134.769 | 89.9479 | -134.769 | 269.948 | HAUT Niveau 2 (Mezzanine 49003) | 1096.1 | 960 | 0 | 1096.13 | 1115.35 | 957.898
Poutre en Acier 1549668 | Niveau 2 | 1549668 | 2 | 0 | 913068333 | 7 | -10 | 2097014839 | 0 | -1 | 1 | 096 | 05 | Niveau 2 | 100.858 | -135.849 | 173.858 | -135.849 | 353.858 | HAUT Niveau 2 (Mezzanine 49003) | 1109 | 970 | 0 | 1108.99 | 1128.21 | 969.134
Poutre en Acier 1549422 | Niveau 2 | 1549422 | 2 | 0 | 913068333 | 7 | -10 | 2097014839 | -200 | 0 | 1 | 095 | 05 | Niveau 2 | 101.084 | -131.603 | 45.5479 | -131.603 | 225.548 | HAUT Niveau 2 (Mezzanine 49003) | 1111.5 | 970 | 0 | 1111.47 | 1130.69 | 971.305
Poutre en Acier 1548878 | Niveau 2 | 1548878 | 2 | 0 | 913068333 | 7 | -10 | 2097014839 | -200 | 0 | 0 | 090 | 05 | Niveau 2 | 39.5994 | -133.25 | 179.869 | -133.25 | 359.869 | HAUT Niveau 2 (Mezzanine 49003) | 435.4 | 380 | 0 | 435.418 | 454.636 | 380.508
Poutre en Acier 1548819 | Niveau 2 | 1548819 | 2 | 0 | 913068333 | 7 | -10 | 2097014839 | -200 | 0 | 1 | 089 | 05 | Niveau 2 | 69.4054 | -133 | 179.869 | -133 | 359.869 | HAUT Niveau 2 (Mezzanine 49003) | 763.2 | 670 | 0 | 763.153 | 782.371 | 666.911
Poutre en Acier 1548960 | Niveau 2 | 1548960 | 2 | 0 | 913068333 | 7 | -10 | 2097014839 | -200 | 0 | 0 | 092 | 05 | Niveau 2 | 99.2024 | -133.25 | 179.666 | -133.25 | 359.666 | HAUT Niveau 2 (Mezzanine 49003) | 1090.8 | 950 | 0 | 1090.79 | 1110 | 953.228
Poutre en Acier 1548919 | Niveau 2 | 1548919 | 2 | 0 | 913068333 | 7 | -10 | 2097014839 | -200 | 0 | 0 | 091 | 05 | Niveau 2 | 39.5994 | -133.25 | 179.869 | -133.25 | 359.869 | HAUT Niveau 2 (Mezzanine 49003) | 435.4 | 380 | 0 | 435.418 | 454.636 | 380.508
Poutre en Acier 1548760 | Niveau 2 | 1548760 | 2 | 0 | 913068333 | 7 | -10 | 2097014839 | -200 | 0 | 1 | 088 | 05 | Niveau 2 | 69.3902 | -133 | 179.869 | -133 | 359.869 | HAUT Niveau 2 (Mezzanine 49003) | 763 | 670 | 0 | 762.985 | 782.203 | 666.765
Poutre en Acier 1548119 | Niveau 2 | 1548119 | 7 | -10 | 2097014839 | 2 | 0 | 913068333 | -200 | 0 | 1 | 085 | 05 | Niveau 2 | 99.7678 | -133.25 | 89.8082 | -133.25 | 269.808 | HAUT Niveau 2 (Mezzanine 49003) | 1097 | 960 | -5.51738e-33 | 1097 | 1116.22 | 958.661
Poutre en Acier 1548640 | Niveau 2 | 1548640 | 2 | 0 | 913068333 | 7 | -10 | 2097014839 | -200 | 0 | 0 | 087 | 05 | Niveau 2 | 98.8096 | -133 | 179.841 | -133 | 359.841 | HAUT Niveau 2 (Mezzanine 49003) | 1086.5 | 950 | 0 | 1086.47 | 1105.69 | 949.453
Poutre en Acier 1548322 | Niveau 2 | 1548322 | 2 | 0 | 913068333 | 7 | -10 | 2097014839 | -200 | 0 | 0 | 086 | 05 | Niveau 2 | 99.5479 | -133 | 179.841 | -133 | 359.841 | HAUT Niveau 2 (Mezzanine 49003) | 1094.6 | 960 | 5.51738e-33 | 1094.59 | 1113.8 | 956.548
Poutre en Acier 2055925 | Niveau 2 | 2055925 | 7 | -10 | 2097014839 | 2 | 0 | 913068333 | -200 | 2 | 1 | 147 | 05 | Niveau 2 | 39.7775 | -133 | 179.869 | -133 | 359.869 | HAUT Niveau 2 (Mezzanine 49003) | 437.4 | 380 | 0 | 437.377 | 456.595 | 382.219
Poutre en Acier 2055808 | Niveau 2 | 2055808 | 7 | -10 | 2097014839 | 2 | 0 | 913068333 | -200 | 2 | 1 | 146 | 05 | Niveau 2 | 39.7958 | -133 | 179.869 | -133 | 359.869 | HAUT Niveau 2 (Mezzanine 49003) | 437.6 | 380 | 0 | 437.578 | 456.796 | 382.395

# IfcBeam: RND 60 (10)
Type - Material: Aluminium mat
Description: Poutre en Acier; Group: ...de matériaux et couleurs = Aluminium mat; ...de profilés en acier = RND 60
__RECOGNIZE__ - TPLG: 214; TPLG_OD: 503; GENERATE: 1; Section_TypeForm: 0; AngleRotaz: 0; Section, Section_NumItems: 1; Section, Section_Item 0, Section_ID: 220; Section, Section_Item 0, Section_Desc: RND 60; Section, Section_Item 0, Section_Categ: 2; Section, Section_Item 0, Section_Tipo: 23; Section, Section_Item 0, Section_Base: 0.06; Section, Section_Item 0, Section_H: 0.06; Section, Section_Item 0, Section_DistPrfX: 0; Section, Section_Item 0, Section_DistPrfY: 0; Section, Section_Item 0, Section_DispInPianta: 0; Section, Section_Item 0, Section_TipoForma: 0; Section, Section_Item 0, Section_AngleRot: 0; Section, Section_Item 0, Section_BrcX: 0; Section, Section_Item 0, Section_BrcY: 0
CTLG_EXTERNAL_LINK - 0, DocType: 2; 0, Tag: 0; 0, Crc: 913068333; 1, DocType: 7; 1, Tag: -10; 1, Crc: 1928387791
IFC_PSET_PolygonOffset - polygonOffsetFactor: 2; polygonOffsetUnits: 2
IFC_Pset_Alignment - Alignment_Sez: 0; Alignment_TS: 1; Alignment_NODO_CLC: 0; Alignment_C_FC_SUP: 0
IFC_Pset_Caractéristiques - Coupe: RND 60
IFC_Pset_Géométrie - Rotation: 0 deg
IFC_Pset_Système de Référence Altimétrique_SUPÉRIEUR - sous Niveau: <aucun>
IFC_Pset_Données Métré - Surface de la Section: 36 cm2; Base Section: 6 cm; Hauteur Section: 6 cm; Diamètre Section: 6 cm
IFC_Pset_Matériaux - Principal: Aluminium mat
Pset_BeamCommon - Reference: RND 60 (..\Profilés\Rond\)
BaseQuantities - CrossSectionArea: 28.2385 cm2
Name | In | __RECOGNIZE__, ID = IFC_Pset_Caractéristiques, ID | Alignment_Poly | Alignment_Nodo | Numérotation | Numéro niveau | Titre niveau | IFC_Pset_Géométrie_P1 (POINT initial), Longueur (cm) = IFC_Pset_Géométrie_P2 (POINT final), Longueur (cm) = Span (cm) = NominalLength (cm) | IFC_Pset_Géométrie_P1 (POINT initial), Cote (cm) = delta (P1) (cm) | IFC_Pset_Géométrie_P1 (POINT initial), Angle XY (deg) | IFC_Pset_Géométrie_P2 (POINT final), Cote (cm) = delta (P2) (cm) | IFC_Pset_Géométrie_P2 (POINT final), Angle XY (deg) | NIVEAU | Surface (latérale) (cm2) | Volume (cm3) | Slope (deg) | OuterSurfaceArea (cm2) | TotalSurfaceArea (cm2) | GrossVolume (cm3) = NetVolume (cm3)
Poutre en Acier 1548116 | Mezzanine | 1548116 | 0 | -1 | 084 | 06 | Mezzanine | 153.701 | 24.7024 | 164.55 | 24.7024 | 344.55 | Mezzanine (Mezzanine 49003) | 2897.2 | 4340 | 0 | 2897.2 | 2953.67 | 4340.28
Poutre en Acier 561511 | Couverture | 561511 | 0 | -1 | 007 | 07 | Couverture | 154.235 | -255 | 15.319 | -255 | 195.319 | Couverture (Couverture 2134) | 2907.3 | 4360 | 0 | 2907.26 | 2963.74 | 4355.36
Poutre en Acier 561508 | Couverture | 561508 | 0 | -1 | 006 | 07 | Couverture | 151.761 | -255 | 45.3071 | -255 | 225.307 | Couverture (Couverture 2134) | 2860.6 | 4290 | 0 | 2860.63 | 2917.11 | 4285.5
Poutre en Acier 561505 | Couverture | 561505 | 0 | -1 | 005 | 07 | Couverture | 147.525 | -255 | 73.7632 | -255 | 253.763 | Couverture (Couverture 2134) | 2780.8 | 4170 | 0 | 2780.79 | 2837.27 | 4165.89
Poutre en Acier 558382 | Couverture | 558382 | 0 | -1 | 002 | 07 | Couverture | 145.819 | -255 | 104.167 | -255 | 284.167 | Couverture (Couverture 2134) | 2748.6 | 4120 | 0 | 2748.63 | 2805.11 | 4117.71
Poutre en Acier 558379 | Couverture | 558379 | -1 | -10 | 001 | 07 | Couverture | 172.533 | -255 | 0.359015 | -255 | 180.359 | Couverture (Couverture 2134) | 3252.2 | 4870 | 0 | 3252.18 | 3308.65 | 4872.08
Poutre en Acier 561502 | Couverture | 561502 | 0 | -1 | 004 | 07 | Couverture | 154.812 | -255 | 136.035 | -255 | 316.035 | Couverture (Couverture 2134) | 2918.1 | 4370 | 0 | 2918.14 | 2974.62 | 4371.65
Poutre en Acier 561499 | Couverture | 561499 | 0 | -1 | 003 | 07 | Couverture | 153.701 | -255 | 164.55 | -255 | 344.55 | Couverture (Couverture 2134) | 2897.2 | 4340 | -7.06225e-31 | 2897.2 | 2953.67 | 4340.28
Poutre en Acier 953673 | Couverture | 953673 | -200 | 6 | 039 | 07 | Couverture | 115.861 | 48 | 133.552 | 45 | 313.552 | Couverture (Couverture 2134) | 2183.9 | 3270 | -1.48373 | 2183.92 | 2240.4 | 3271.73
Poutre en Acier 953676 | Couverture | 953676 | -200 | 6 | 040 | 07 | Couverture | 330.512 | 0 | 10.7569 | -8 | 190.757 | Couverture (Couverture 2134) | 6230 | 9330 | -1.38697 | 6230 | 6286.47 | 9333.14

# IfcBeam: Ø100 (30)
In: Rez-de-Jardin
Type - Material: Chêne rouvre 02
Description: Poutre; Group: ...de matériaux et couleurs = Chêne rouvre 02; ...de sections pour tiges = Ø100
__RECOGNIZE__ - TPLG: 210; TPLG_OD: 501; GENERATE: 1; Section_TypeForm: 0; AngleRotaz: 0; Section, Section_NumItems: 1; Section, Section_Item 0, Section_ID: 106; Section, Section_Item 0, Section_Desc: Ø100,00; Section, Section_Item 0, Section_Categ: 3; Section, Section_Item 0, Section_Tipo: 2; Section, Section_Item 0, Section_Base: 0.1; Section, Section_Item 0, Section_H: 0.1; Section, Section_Item 0, Section_DistPrfX: 0; Section, Section_Item 0, Section_DistPrfY: 0; Section, Section_Item 0, Section_DispInPianta: 0; Section, Section_Item 0, Section_TipoForma: 0; Section, Section_Item 0, Section_AngleRot: 0; Section, Section_Item 0, Section_BrcX: 0; Section, Section_Item 0, Section_BrcY: 0
CTLG_EXTERNAL_LINK - 0, DocType: 2; 0, Tag: 0; 0, Crc: -1439514055; 1, DocType: 6; 1, Tag: -10; 1, Crc: -1016240577
IFC_PSET_PolygonOffset - polygonOffsetFactor: 2; polygonOffsetUnits: 2
IFC_Pset_Alignment - Alignment_Sez: 0; Alignment_Poly: -1; Alignment_Nodo: 1; Alignment_NODO_CLC: 0; Alignment_C_FC_SUP: 0
IFC_Pset_Caractéristiques - Numéro niveau: 02; Titre niveau: Rez-de-Jardin; Coupe: Ø100
IFC_Pset_Géométrie - Rotation: 0 deg
IFC_Pset_Système de Référence Altimétrique_SUPÉRIEUR - NIVEAU: HAUT Rez-de-Jardin (Rez-de-chaussée 1047); sous Niveau: <aucun>
IFC_Pset_Données Métré - Surface de la Section: 100 cm2; Base Section: 10 cm; Hauteur Section: 10 cm; Diamètre Section: 10 cm
IFC_Pset_Matériaux - Principal: Chêne rouvre 02
Pset_BeamCommon - Reference: Ø100 (..\Section circulaire\)
BaseQuantities - CrossSectionArea: 78.4402 cm2
Name | __RECOGNIZE__, ID = IFC_Pset_Caractéristiques, ID | Alignment_TS | Numérotation | IFC_Pset_Géométrie_P1 (POINT initial), Longueur (cm) = IFC_Pset_Géométrie_P2 (POINT final), Longueur (cm) = Span (cm) = NominalLength (cm) | IFC_Pset_Géométrie_P1 (POINT initial), Cote (cm) = delta (P1) (cm) | IFC_Pset_Géométrie_P1 (POINT initial), Angle XY (deg) | IFC_Pset_Géométrie_P2 (POINT final), Cote (cm) = delta (P2) (cm) | IFC_Pset_Géométrie_P2 (POINT final), Angle XY (deg) | Surface (latérale) (cm2) | Volume (cm3) | Slope (deg) | OuterSurfaceArea (cm2) | TotalSurfaceArea (cm2) | GrossVolume (cm3) = NetVolume (cm3)
Poutre 1702948 | 1702948 | 1 | 022 | 143.81 | -151 | 179.535 | -152 | 359.535 | 4500 | 10000 | -0.398415 | 4517.94 | 4674.82 | 11280.5
Poutre 1702945 | 1702945 | 1 | 021 | 154.346 | -153.5 | 3.19097 | -153 | 183.191 | 4800 | 10000 | 0.185609 | 4848.91 | 5005.79 | 12106.9
Poutre 1703021 | 1703021 | 1 | 024 | 186.47 | -155 | 88.5371 | -156.5 | 268.537 | 5900 | 10000 | -0.460903 | 5858.12 | 6015 | 14626.7
Poutre 1703018 | 1703018 | 1 | 023 | 180.597 | -151 | 88.4911 | -155 | 268.491 | 5700 | 10000 | -1.26913 | 5673.62 | 5830.5 | 14166.1
Poutre 1702936 | 1702936 | 1 | 018 | 185.751 | -157 | 1.29388 | -156 | 181.294 | 5800 | 10000 | 0.308456 | 5835.54 | 5992.42 | 14570.3
Poutre 1702933 | 1702933 | 1 | 017 | 186.436 | -156 | 178.902 | -157 | 358.902 | 5900 | 10000 | -0.307323 | 5857.07 | 6013.95 | 14624.1
Poutre 1702942 | 1702942 | 1 | 020 | 142.345 | -154 | 177.618 | -154 | 357.618 | 4500 | 10000 | 0 | 4471.9 | 4628.78 | 11165.6
Poutre 1702939 | 1702939 | 1 | 019 | 150.663 | -155 | 179.819 | -156 | 359.819 | 4700 | 10000 | -0.380294 | 4733.21 | 4890.09 | 11818
Poutre 1703098 | 1703098 | 1 | 030 | 190.295 | -160 | 89.3513 | -160 | 269.351 | 6000 | 10000 | 0 | 5978.29 | 6135.17 | 14926.8
Poutre 1703078 | 1703078 | 1 | 029 | 228.016 | -152.5 | 150 | -155 | 330 | 7200 | 20000 | -0.628211 | 7163.34 | 7320.22 | 17885.6
Poutre 1703108 | 1703108 | 1 | 032 | 119.471 | -161 | 0 | -161 | 180 | 3800 | 10000 | 0 | 3753.28 | 3910.16 | 9371.31
Poutre 1703103 | 1703103 | 1 | 031 | 179.594 | -160 | 88.0707 | -163 | 268.071 | 5600 | 10000 | -0.957134 | 5642.11 | 5798.99 | 14087.4
Poutre 1703027 | 1703027 | 0 | 026 | 222.699 | -161 | 153.695 | -161 | 333.695 | 7000 | 20000 | 0 | 6996.3 | 7153.18 | 17468.6
Poutre 1703024 | 1703024 | 1 | 025 | 181.764 | -156 | 89.5553 | -157 | 269.555 | 5700 | 10000 | -0.315222 | 5710.3 | 5867.18 | 14257.6
Poutre 1703072 | 1703072 | 1 | 028 | 117.804 | -157 | 151.429 | -156 | 331.429 | 3700 | 10000 | 0.486372 | 3700.91 | 3857.79 | 9240.55
Poutre 1703030 | 1703030 | 0 | 027 | 230.639 | -156 | 153.2 | -159 | 333.2 | 7200 | 20000 | -0.745287 | 7245.74 | 7402.62 | 18091.4
Poutre 1702841 | 1702841 | 1 | 006 | 183.176 | -158 | 178.89 | -155.5 | 358.89 | 5800 | 10000 | 0.782 | 5754.65 | 5911.53 | 14368.4
Poutre 1702838 | 1702838 | 1 | 005 | 181.626 | -156 | 0.0473322 | -156 | 180.047 | 5700 | 10000 | 0 | 5705.94 | 5862.82 | 14246.7
Poutre 1702853 | 1702853 | 1 | 008 | 187.226 | -158 | 179.867 | -158 | 359.867 | 5900 | 10000 | 0 | 5881.89 | 6038.77 | 14686.1
Poutre 1702850 | 1702850 | 1 | 007 | 183.539 | -159 | 179.688 | -158 | 359.688 | 5800 | 10000 | 0.312173 | 5766.06 | 5922.94 | 14396.9
Poutre 1702835 | 1702835 | 1 | 004 | 171.045 | -159 | 0.558791 | -156 | 180.559 | 5400 | 10000 | 1.00498 | 5373.54 | 5530.42 | 13416.8
Poutre 1702924 | 1702924 | 1 | 014 | 181.836 | -161 | 0.559816 | -161 | 180.56 | 5700 | 10000 | -2.20695e-32 | 5712.55 | 5869.43 | 14263.3
Poutre 1702921 | 1702921 | 1 | 013 | 186.648 | -161 | 0.44547 | -161 | 180.445 | 5900 | 10000 | 0 | 5863.71 | 6020.59 | 14640.7
Poutre 1702930 | 1702930 | 1 | 016 | 183.828 | -157 | 179.871 | -159 | 359.871 | 5800 | 10000 | -0.623375 | 5775.13 | 5932.01 | 14419.5
Poutre 1702927 | 1702927 | 1 | 015 | 189.551 | -160 | 179.79 | -160 | 359.79 | 6000 | 10000 | 0 | 5954.93 | 6111.81 | 14868.4
Poutre 1702903 | 1702903 | 1 | 010 | 20 | -159 | 9.93493 | -159 | 189.935 | 600 | 0 | 0 | 628.319 | 785.199 | 1568.8
Poutre 1702893 | 1702893 | 1 | 009 | 80.7125 | -159 | 2.47933 | -159 | 182.479 | 2500 | 10000 | 0 | 2535.66 | 2692.54 | 6331.1
Poutre 1702918 | 1702918 | 1 | 012 | 132.949 | -161 | 178.949 | -160 | 358.949 | 4200 | 10000 | 0.430965 | 4176.71 | 4333.59 | 10428.5
Poutre 1702915 | 1702915 | 1 | 011 | 20 | -160 | 172.245 | -160 | 352.245 | 600 | 0 | -3.53113e-31 | 628.319 | 785.199 | 1568.8
Poutre 1703117 | 1703117 | 1 | 033 | 184.388 | -162 | 88.8523 | -162 | 268.852 | 5800 | 10000 | 0 | 5792.73 | 5949.61 | 14463.4

# IfcBuildingElementProxy (52)
__RECOGNIZE__ - GENERATE: 1
CTLG_EXTERNAL_LINK - 0, DocType: 2
IFC_PSET_PolygonOffset - polygonOffsetFactor: 2; polygonOffsetUnits: 2
IFC_Pset_Système de Référence Altimétrique_INFÉRIEUR - sous Niveau: <aucun>
Name | In | Material | __RECOGNIZE__, ID = IFC_Pset_Caractéristiques, ID | TPLG | TPLG_OD | 0, Tag | 0, Crc | Numérotation | Numéro niveau | Titre niveau | IFC_Pset_Géométrie, Hauteur (cm) | NIVEAU | delta (cm) | delta (P1) (cm) | delta (P2) (cm) | Périmètre (cm) | Surface en Plan (cm2) | Surface Parois (cm2) | Volume (cm3) | Principal | Group
Encombrement 1003432 | Default Site | Pierre de sarnico | 1003432 | 9014 | 9014 | 0 | -1568333279 | 29 | 06 | Mezzanine | 32 | Mezzanine (Mezzanine 49003) | -11 | -11 | 0 | 109 | 700 | 3500 | 20000 | Pierre de sarnico | ...de matériaux et couleurs = Pierre de sarnico
Arbre 1824244 | Rez-de-Jardin | <Nuovo Albero...> Prospetto | 1824244 | 806 | 806 | 100 | 912113680 | 03 | 02 | Rez-de-Jardin |  | Rez-de-Jardin (Rez-de-Jardin 15545) | 113.288 |  |  |  |  |  |  |  | ...de matériaux et couleurs = AM113_062_Tilia_Bark_Color; ...de matériaux et couleurs - 1 = AM113_062_Tilia_Color; ...de matériaux et couleurs - 2 = <Nuovo Albero...> Prospetto; ...de arbres = Tilleul à petites feuilles | CTLG_EXTERNAL_LINK - 1, DocType: 2; 1, Tag: 101; 1, Crc: 776722610; 2, DocType: 2; 2, Tag: 2015; 2, Crc: 503494118; 3, DocType: 8; 3, Tag: 0; 3, Crc: -1805778534; IFC_Pset_Caractéristiques - Arbre: Tilleul à petites feuilles; Hauteur: 1200 cm; Pset_BuildingElementProxyCommon - Reference: Tilleul à petites feuilles (..\Arbres\)
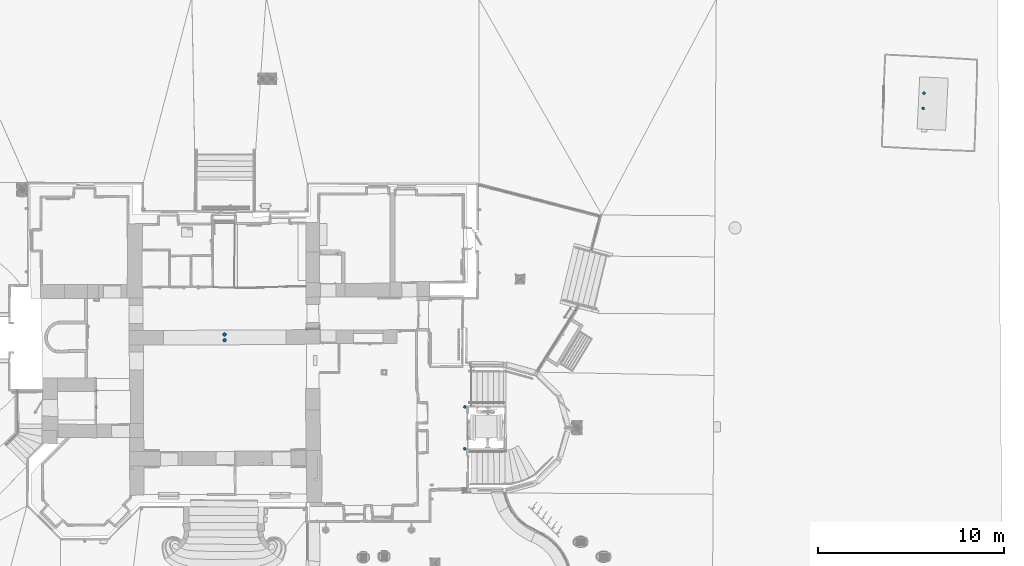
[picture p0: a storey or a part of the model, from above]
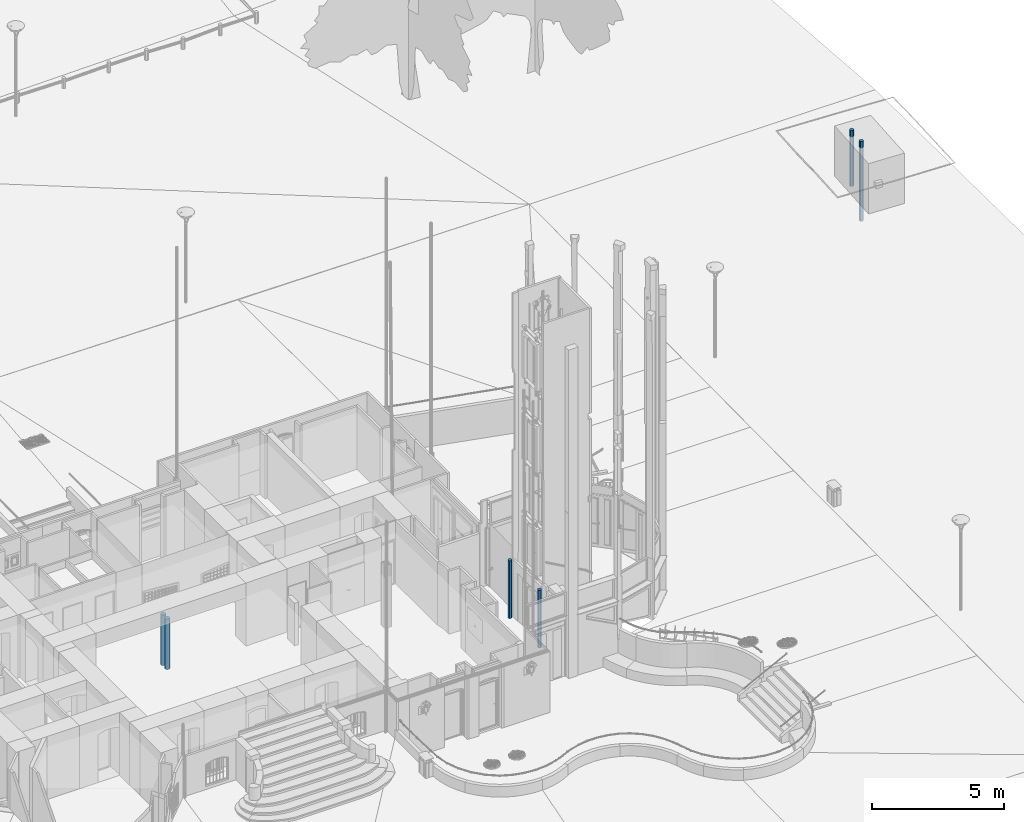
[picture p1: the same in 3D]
Properties of the parts of a building model (IFC2X3), part 3 of 37

# IfcBuildingElementProxy (52)
Name | In | Material | __RECOGNIZE__, ID = IFC_Pset_Caractéristiques, ID | TPLG | TPLG_OD | 0, Tag | 0, Crc | Numérotation | Numéro niveau | Titre niveau | IFC_Pset_Géométrie, Hauteur (cm) | NIVEAU | delta (cm) | delta (P1) (cm) | delta (P2) (cm) | Périmètre (cm) | Surface en Plan (cm2) | Surface Parois (cm2) | Volume (cm3) | Principal | Group
Arbre 1824243 | Rez-de-Jardin | <New Tree...> Elevation View | 1824243 | 806 | 806 | 100 | 52160030 | 02 | 02 | Rez-de-Jardin |  | Rez-de-Jardin (Rez-de-Jardin 15545) | 113.288 |  |  |  |  |  |  |  | ...de matériaux et couleurs = Vegetation_Bark_Ponderosa; ...de matériaux et couleurs - 1 = Material2; ...de matériaux et couleurs - 2 = Material4; ...de matériaux et couleurs - 3 = <New Tree...> Elevation View; ...de arbres = Optimised Maple Tree | CTLG_EXTERNAL_LINK - 1, DocType: 2; 1, Tag: 101; 1, Crc: -414708822; 2, DocType: 2; 2, Tag: 102; 2, Crc: 731347634; 3, DocType: 2; 3, Tag: 2015; 3, Crc: -1036197153; 4, DocType: 8; 4, Tag: 0; 4, Crc: -689097959; IFC_Pset_Caractéristiques - Arbre: Optimised Maple Tree; Hauteur: 1200 cm; Pset_BuildingElementProxyCommon - Reference: Optimised Maple Tree (..\Arbres\)
Arbre 303642 | Rez-de-Jardin | <Nouvel Arbre...> Élévation | 303642 | 806 | 806 | 100 | -471767257 | 01 | 02 | Rez-de-Jardin |  | Rez-de-Jardin (Rez-de-Jardin 15545) | 113.288 |  |  |  |  |  |  |  | ...de matériaux et couleurs = feuilles 1; ...de matériaux et couleurs - 1 = Tronc_Pin; ...de matériaux et couleurs - 2 = Couleur_E01; ...de matériaux et couleurs - 3 = <Nouvel Arbre...> Élévation; ...de arbres = Sapin | CTLG_EXTERNAL_LINK - 1, DocType: 2; 1, Tag: 101; 1, Crc: -1832560469; 2, DocType: 2; 2, Tag: 102; 2, Crc: 1537484321; 3, DocType: 2; 3, Tag: 2015; 3, Crc: -1649747185; 4, DocType: 8; 4, Tag: 0; 4, Crc: -1003470859; IFC_Pset_Caractéristiques - Arbre: Sapin; Hauteur: 1200 cm; Pset_BuildingElementProxyCommon - Reference: Sapin (..\Arbres\)
Encombrement 959293 | Rez-de-Jardin | Blanc | 959293 | 9014 | 9014 | 0 | -746779066 | 27 | 02 | Rez-de-Jardin | 42 | Rez-de-Jardin (Rez-de-Jardin 15545) | 240 | 240 | 0 | 115 | 800 | 4800 | 30000 | Blanc | ...de matériaux et couleurs = Blanc
Encombrement 503479 | Rez-de-Jardin | Blanc | 503479 | 9014 | 9014 | 0 | -746779066 | 26 | 02 | Rez-de-Jardin | 1414.2 | Rez-de-Jardin (Rez-de-Jardin 15545) | 106 | 106 | 0 | 40 | 100 | 56600 | 140000 | Blanc | ...de matériaux et couleurs = Blanc
Encombrement 503080 | Rez-de-Jardin | Blanc | 503080 | 9014 | 9014 | 0 | -746779066 | 25 | 02 | Rez-de-Jardin | 1414.2 | Rez-de-Jardin (Rez-de-Jardin 15545) | 106 | 106 | 0 | 40 | 100 | 57100 | 140000 | Blanc | ...de matériaux et couleurs = Blanc
Encombrement 1824236 | Rez-de-Jardin | Blanc | 1824236 | 9014 | 9014 | 0 | -746779066 | 48 | 02 | Rez-de-Jardin | 26 | Rez-de-Jardin (Rez-de-Jardin 15545) | 225 | 225 | 0 | 86 | 400 | 2200 | 10000 | Blanc | ...de matériaux et couleurs = Blanc
Encombrement 1824235 | Rez-de-Jardin | Blanc | 1824235 | 9014 | 9014 | 0 | -746779066 | 47 | 02 | Rez-de-Jardin | 340.138 | Rez-de-Jardin (Rez-de-Jardin 15545) | 0 | 0 | 0 | 868 | 43100 | 295300 | 14640000 | Blanc | ...de matériaux et couleurs = Blanc
Encombrement 1702009 | Rez-de-Jardin | Blanc | 1702009 | 9014 | 9014 | 0 | -746779066 | 46 | 02 | Rez-de-Jardin | 85 | Rez-de-Jardin (Rez-de-Jardin 15545) | 65 | 65 | 0 | 147 | 1100 | 12500 | 90000 | Blanc | ...de matériaux et couleurs = Blanc
Encombrement 345563 | Rez-de-Jardin | Blanc | 345563 | 9014 | 9014 | 0 | -746779066 | 09 | 02 | Rez-de-Jardin | 60.0004 | Rez-de-Jardin (Rez-de-Jardin 15545) | 161 | 161 | 0 | 111 | 900 | 6700 | 50000 | Blanc | ...de matériaux et couleurs = Blanc
Encombrement 336581 | Rez-de-Jardin | Blanc | 336581 | 9014 | 9014 | 0 | -746779066 | 08 | 02 | Rez-de-Jardin | 61.0875 | Rez-de-Jardin (Rez-de-Jardin 15545) | 161 | 161 | 0 | 106 | 800 | 6500 | 50000 | Blanc | ...de matériaux et couleurs = Blanc
Encombrement 322631 | Rez-de-Jardin | Blanc | 322631 | 9014 | 9014 | 0 | -746779066 | 07 | 02 | Rez-de-Jardin | 125 | Rez-de-Jardin (Rez-de-Jardin 15545) | 0 | 0 | 0 | 117 | 1000 | 14700 | 120000 | Blanc | ...de matériaux et couleurs = Blanc
Encombrement 348051 | Rez-de-Jardin | Béton (01) | 348051 | 9014 | 9014 | 0 | -1434640612 | 12 | 02 | Rez-de-Jardin | 11.2277 | Rez-de-Jardin (Rez-de-Jardin 15545) | 128 | 128 | 0 | 270 | 4700 | 3000 | 50000 | Béton (01) | ...de matériaux et couleurs = Béton (01)
Encombrement 348050 | Rez-de-Jardin | Béton (01) | 348050 | 9014 | 9014 | 0 | -1434640612 | 11 | 02 | Rez-de-Jardin | 5.3 | Rez-de-Jardin (Rez-de-Jardin 15545) | 123 | 123 | 0 | 372 | 8500 | 2000 | 50000 | Béton (01) | ...de matériaux et couleurs = Béton (01)
Encombrement 345566 | Rez-de-Jardin | Béton (01) | 345566 | 9014 | 9014 | 0 | -1434640612 | 10 | 02 | Rez-de-Jardin | 22.8638 | Rez-de-Jardin (Rez-de-Jardin 15545) | 100 | 100 | 0 | 343 | 7500 | 7800 | 170000 | Béton (01) | ...de matériaux et couleurs = Béton (01)
Encombrement 78464 | Rez-de-Jardin | Blanc | 78464 | 9014 | 9014 | 0 | -746779066 | 03 | 02 | Rez-de-Jardin | 119.4 | Rez-de-Jardin (Rez-de-Jardin 15545) | 94 | 94 | 0 | 320 | 4800 | 38200 | 570000 | Blanc | ...de matériaux et couleurs = Blanc
Encombrement 78043 | Rez-de-Jardin | Blanc | 78043 | 9014 | 9014 | 0 | -746779066 | 02 | 02 | Rez-de-Jardin | 197.109 | Rez-de-Jardin (Rez-de-Jardin 15545) | 18 | 18 | 0 | 145 | 1000 | 28500 | 190000 | Blanc | ...de matériaux et couleurs = Blanc
Encombrement 78032 | Rez-de-Jardin | Blanc | 78032 | 9014 | 9014 | 0 | -746779066 | 01 | 02 | Rez-de-Jardin | 33 | Rez-de-Jardin (Rez-de-Jardin 15545) | 0 | 0 | 0 | 229 | 3300 | 7600 | 110000 | Blanc | ...de matériaux et couleurs = Blanc
Encombrement 322630 | Rez-de-Jardin | Blanc | 322630 | 9014 | 9014 | 0 | -746779066 | 06 | 02 | Rez-de-Jardin | 125 | Rez-de-Jardin (Rez-de-Jardin 15545) | 0 | 0 | 0 | 110 | 800 | 13800 | 100000 | Blanc | ...de matériaux et couleurs = Blanc
Encombrement 348060 | Rez-de-Jardin | Béton (01) | 348060 | 9014 | 9014 | 0 | -1434640612 | 21 | 02 | Rez-de-Jardin | 5.5915 | Rez-de-Jardin (Rez-de-Jardin 15545) | 155.5 | 155.5 | 0 | 211 | 2800 | 1200 | 20000 | Béton (01) | ...de matériaux et couleurs = Béton (01)
Encombrement 348059 | Rez-de-Jardin | Béton (01) | 348059 | 9014 | 9014 | 0 | -1434640612 | 20 | 02 | Rez-de-Jardin | 10.5915 | Rez-de-Jardin (Rez-de-Jardin 15545) | 145 | 145 | 0 | 190 | 2300 | 2000 | 20000 | Béton (01) | ...de matériaux et couleurs = Béton (01)
Encombrement 348058 | Rez-de-Jardin | Béton (01) | 348058 | 9014 | 9014 | 0 | -1434640612 | 19 | 02 | Rez-de-Jardin | 5.32767 | Rez-de-Jardin (Rez-de-Jardin 15545) | 139.4 | 139.4 | 0 | 295 | 5400 | 1600 | 30000 | Béton (01) | ...de matériaux et couleurs = Béton (01)
Encombrement 348054 | Rez-de-Jardin | Béton (01) | 348054 | 9014 | 9014 | 0 | -1434640612 | 15 | 02 | Rez-de-Jardin | 5.4915 | Rez-de-Jardin (Rez-de-Jardin 15545) | 155.6 | 155.6 | 0 | 200 | 2500 | 1100 | 10000 | Béton (01) | ...de matériaux et couleurs = Béton (01)
Encombrement 348053 | Rez-de-Jardin | Béton (01) | 348053 | 9014 | 9014 | 0 | -1434640612 | 14 | 02 | Rez-de-Jardin | 10.7915 | Rez-de-Jardin (Rez-de-Jardin 15545) | 144.8 | 144.8 | 0 | 181 | 2100 | 2000 | 20000 | Béton (01) | ...de matériaux et couleurs = Béton (01)
Encombrement 348052 | Rez-de-Jardin | Béton (01) | 348052 | 9014 | 9014 | 0 | -1434640612 | 13 | 02 | Rez-de-Jardin | 5.72767 | Rez-de-Jardin (Rez-de-Jardin 15545) | 139 | 139 | 0 | 291 | 5400 | 1700 | 30000 | Béton (01) | ...de matériaux et couleurs = Béton (01)
Encombrement 348057 | Rez-de-Jardin | Béton (01) | 348057 | 9014 | 9014 | 0 | -1434640612 | 18 | 02 | Rez-de-Jardin | 10.9277 | Rez-de-Jardin (Rez-de-Jardin 15545) | 128.3 | 128.3 | 0 | 273 | 4700 | 3000 | 50000 | Béton (01) | ...de matériaux et couleurs = Béton (01)
Encombrement 348056 | Rez-de-Jardin | Béton (01) | 348056 | 9014 | 9014 | 0 | -1434640612 | 17 | 02 | Rez-de-Jardin | 5.16383 | Rez-de-Jardin (Rez-de-Jardin 15545) | 123.2 | 123.2 | 0 | 368 | 8000 | 1900 | 40000 | Béton (01) | ...de matériaux et couleurs = Béton (01)
Encombrement 348055 | Rez-de-Jardin | Béton (01) | 348055 | 9014 | 9014 | 0 | -1434640612 | 16 | 02 | Rez-de-Jardin | 10.8638 | Rez-de-Jardin (Rez-de-Jardin 15545) | 112 | 112 | 0 | 343 | 7100 | 3700 | 80000 | Béton (01) | ...de matériaux et couleurs = Béton (01)
Encombrement 449722 | Niveau 1 | Blanc | 449722 | 9014 | 9014 | 0 | -746779066 | 24 | 04 | Niveau 1 | 20.6159 | Niveau 1 (Niveau 1 2343) | 85 | 85 | 0 | 132 | 1300 | 2700 | 30000 | Blanc | ...de matériaux et couleurs = Blanc
Encombrement 449721 | Niveau 1 | Blanc | 449721 | 9014 | 9014 | 0 | -746779066 | 23 | 04 | Niveau 1 | 20.6159 | Niveau 1 (Niveau 1 2343) | 85 | 85 | 0 | 132 | 1300 | 2700 | 30000 | Blanc | ...de matériaux et couleurs = Blanc
Encombrement 449719 | Niveau 1 | Blanc | 449719 | 9014 | 9014 | 0 | -746779066 | 22 | 04 | Niveau 1 | 20.6159 | Niveau 1 (Niveau 1 2343) | 85 | 85 | 0 | 132 | 1300 | 2700 | 30000 | Blanc | ...de matériaux et couleurs = Blanc
Voûte 1824230 | Niveau 2 | Blanc | 1824230 | 8104 | 9121 | 0 | -746779066 | 01 | 05 | Niveau 2 |  | Niveau 2 (Niveau 2 13545) | 230 |  |  |  |  |  |  |  | ...de matériaux et couleurs = Blanc; ...de matériaux et couleurs - 1 = Blanc; ...de matériaux et couleurs - 2 = Blanc; ...de stratigraphies = default; ...de matériaux et couleurs - 3 = Blanc | CTLG_EXTERNAL_LINK - 1, DocType: 2; 1, Tag: 2; 1, Crc: -746779066; 2, DocType: 2; 2, Tag: 3; 2, Crc: -746779066; 3, DocType: 2; 3, Tag: 4; 3, Crc: -746779066; 4, DocType: 9; 4, Tag: 101; 4, Crc: -1895805156; IFC_Pset_Données Métré - Surface intérieure voûtes: 317500 cm2; Surface extérieure voûtes: 323900 cm2; Volume voûtes: 1580000 cm3; Volume remplissages: 0 cm3; IFC_Pset_Matériaux - Extrados: Blanc; Intrados: Blanc; Profils: Blanc; Remplissages: Blanc; IFC_Pset_Aspect_Lignes - Couleur: 0
Encombrement 1005747 | Mezzanine | Pierre de sarnico | 1005747 | 9014 | 9014 | 0 | -1568333279 | 33 | 06 | Mezzanine | 32 | Mezzanine (Mezzanine 49003) | -11 | -11 | 0 | 109 | 700 | 3500 | 20000 | Pierre de sarnico | ...de matériaux et couleurs = Pierre de sarnico
Encombrement 1005746 | Mezzanine | Pierre de sarnico | 1005746 | 9014 | 9014 | 0 | -1568333279 | 32 | 06 | Mezzanine | 32 | Mezzanine (Mezzanine 49003) | -11 | -11 | 0 | 109 | 700 | 3500 | 20000 | Pierre de sarnico | ...de matériaux et couleurs = Pierre de sarnico
Encombrement 1005743 | Mezzanine | Pierre de sarnico | 1005743 | 9014 | 9014 | 0 | -1568333279 | 31 | 06 | Mezzanine | 32 | Mezzanine (Mezzanine 49003) | -11 | -11 | 0 | 109 | 700 | 3500 | 20000 | Pierre de sarnico | ...de matériaux et couleurs = Pierre de sarnico
Encombrement 1014000 | Mezzanine | Pierre de sarnico | 1014000 | 9014 | 9014 | 0 | -1568333279 | 36 | 06 | Mezzanine | 32 | Mezzanine (Mezzanine 49003) | -11 | -11 | 0 | 109 | 700 | 3500 | 20000 | Pierre de sarnico | ...de matériaux et couleurs = Pierre de sarnico
Encombrement 1012990 | Mezzanine | Pierre de sarnico | 1012990 | 9014 | 9014 | 0 | -1568333279 | 35 | 06 | Mezzanine | 32 | Mezzanine (Mezzanine 49003) | -11 | -11 | 0 | 109 | 700 | 3500 | 20000 | Pierre de sarnico | ...de matériaux et couleurs = Pierre de sarnico
Encombrement 1012989 | Mezzanine | Pierre de sarnico | 1012989 | 9014 | 9014 | 0 | -1568333279 | 34 | 06 | Mezzanine | 32 | Mezzanine (Mezzanine 49003) | -11 | -11 | 0 | 109 | 700 | 3500 | 20000 | Pierre de sarnico | ...de matériaux et couleurs = Pierre de sarnico
Encombrement 1005742 | Mezzanine | Pierre de sarnico | 1005742 | 9014 | 9014 | 0 | -1568333279 | 30 | 06 | Mezzanine | 32 | Mezzanine (Mezzanine 49003) | -11 | -11 | 0 | 109 | 700 | 3500 | 20000 | Pierre de sarnico | ...de matériaux et couleurs = Pierre de sarnico
Encombrement 1002954 | Mezzanine | Pierre de sarnico | 1002954 | 9014 | 9014 | 0 | -1568333279 | 28 | 06 | Mezzanine | 32 | Mezzanine (Mezzanine 49003) | -11 | -11 | 0 | 109 | 700 | 3500 | 20000 | Pierre de sarnico | ...de matériaux et couleurs = Pierre de sarnico
Encombrement 1149555 | Mezzanine | Pierre de sarnico | 1149555 | 9014 | 9014 | 0 | -1568333279 | 45 | 06 | Mezzanine | 32 | Mezzanine (Mezzanine 49003) | -8 | -8 | 0 | 109 | 700 | 3500 | 20000 | Pierre de sarnico | ...de matériaux et couleurs = Pierre de sarnico
Encombrement 1149554 | Mezzanine | Pierre de sarnico | 1149554 | 9014 | 9014 | 0 | -1568333279 | 44 | 06 | Mezzanine | 32 | Mezzanine (Mezzanine 49003) | -8 | -8 | 0 | 109 | 700 | 3500 | 20000 | Pierre de sarnico | ...de matériaux et couleurs = Pierre de sarnico
Encombrement 1018900 | Mezzanine | Pierre de sarnico | 1018900 | 9014 | 9014 | 0 | -1568333279 | 43 | 06 | Mezzanine | 32 | Mezzanine (Mezzanine 49003) | -11 | -11 | 0 | 109 | 700 | 3500 | 20000 | Pierre de sarnico | ...de matériaux et couleurs = Pierre de sarnico
Encombrement 1015089 | Mezzanine | Pierre de sarnico | 1015089 | 9014 | 9014 | 0 | -1568333279 | 39 | 06 | Mezzanine | 32 | Mezzanine (Mezzanine 49003) | -11 | -11 | 0 | 109 | 700 | 3500 | 20000 | Pierre de sarnico | ...de matériaux et couleurs = Pierre de sarnico
Encombrement 1015088 | Mezzanine | Pierre de sarnico | 1015088 | 9014 | 9014 | 0 | -1568333279 | 38 | 06 | Mezzanine | 32 | Mezzanine (Mezzanine 49003) | -11 | -11 | 0 | 109 | 700 | 3500 | 20000 | Pierre de sarnico | ...de matériaux et couleurs = Pierre de sarnico
Encombrement 1014001 | Mezzanine | Pierre de sarnico | 1014001 | 9014 | 9014 | 0 | -1568333279 | 37 | 06 | Mezzanine | 32 | Mezzanine (Mezzanine 49003) | -11 | -11 | 0 | 109 | 700 | 3500 | 20000 | Pierre de sarnico | ...de matériaux et couleurs = Pierre de sarnico
Encombrement 1018899 | Mezzanine | Pierre de sarnico | 1018899 | 9014 | 9014 | 0 | -1568333279 | 42 | 06 | Mezzanine | 32 | Mezzanine (Mezzanine 49003) | -11 | -11 | 0 | 109 | 700 | 3500 | 20000 | Pierre de sarnico | ...de matériaux et couleurs = Pierre de sarnico
Encombrement 1015990 | Mezzanine | Pierre de sarnico | 1015990 | 9014 | 9014 | 0 | -1568333279 | 41 | 06 | Mezzanine | 32 | Mezzanine (Mezzanine 49003) | -8 | -8 | 0 | 109 | 700 | 3500 | 20000 | Pierre de sarnico | ...de matériaux et couleurs = Pierre de sarnico
Encombrement 1015989 | Mezzanine | Pierre de sarnico | 1015989 | 9014 | 9014 | 0 | -1568333279 | 40 | 06 | Mezzanine | 32 | Mezzanine (Mezzanine 49003) | -8 | -8 | 0 | 109 | 700 | 3500 | 20000 | Pierre de sarnico | ...de matériaux et couleurs = Pierre de sarnico
Encombrement 197579 | Mezzanine | Aluminium mat | 197579 | 9014 | 9014 | 0 | 913068333 | 05 | 06 | Mezzanine | 56.8004 | Mezzanine (Mezzanine 49003) | 45 | 45 | 0 | 241 | 3600 | 13700 | 210000 | Aluminium mat | ...de matériaux et couleurs = Aluminium mat
Encombrement 197578 | Mezzanine | Aluminium mat | 197578 | 9014 | 9014 | 0 | 913068333 | 04 | 06 | Mezzanine | 106.303 | Mezzanine (Mezzanine 49003) | 54 | 54 | 0 | 225 | 3100 | 23900 | 330000 | Aluminium mat | ...de matériaux et couleurs = Aluminium mat

# IfcBuildingElementProxy: Banc en bois et métal, Bloc 3D 303635
In: Rez-de-Jardin
Type - Material: Béton (01), Sapin blanc, Gris lumière
__RECOGNIZE__ - ID: 303635; TPLG: 820; TPLG_OD: 820; GENERATE: 1
CTLG_EXTERNAL_LINK - 0, DocType: 12; 0, Tag: 2; 0, Crc: -1356789240; 1, DocType: 2; 1, Tag: 100; 1, Crc: 1908701706; 2, DocType: 2; 2, Tag: 101; 2, Crc: -1434640612; 3, DocType: 2; 3, Tag: 102; 3, Crc: -1637103103
IFC_PSET_PolygonOffset - polygonOffsetFactor: 2; polygonOffsetUnits: 2
IFC_Pset_Caractéristiques - ID: 303635; Numérotation: 39; Numéro niveau: 02; Titre niveau: Rez-de-Jardin; Modèle: Banc en bois et métal
IFC_Pset_Système de Référence Altimétrique_INFÉRIEUR - NIVEAU: Rez-de-Jardin (Rez-de-Jardin 15545); delta: 110 cm; sous Niveau: <aucun>
Pset_BuildingElementProxyCommon - Reference: Banc en bois et métal (..\Aménagement urbain\Bancs et Pots\)
Group: ...de matériaux et couleurs - 1 = Béton (01); ...de matériaux et couleurs = Gris lumière; ...de blocs 3d = Banc en bois et métal; ...de matériaux et couleurs - 2 = Sapin blanc

# IfcBuildingElementProxy: Base [P02] 80x80mm (4)
In: Niveau 1
Type - Material: Aluminium mat
__RECOGNIZE__ - TPLG: 273; TPLG_OD: 273; GENERATE: 1
IFC_PSET_PolygonOffset - polygonOffsetFactor: 2; polygonOffsetUnits: 2
IFC_Pset_Caractéristiques_Profil - Profil: Base [P02] 80x80mm; Rotation: 90; Symétrie: no
IFC_Pset_Caractéristiques - Décalage: [0,00; 0,00] mm; Numéro niveau: 04; Titre niveau: Niveau 1
IFC_Pset_Géométrie - Fermé: no
IFC_Pset_Système de Référence Altimétrique_INFÉRIEUR - NIVEAU: Niveau 1 (Niveau 1 2343); delta: 0 cm; sous Niveau: <aucun>
IFC_Pset_Données Métré - Longueur (totale): 159.6 cm; Largeur section: 8 cm; Hauteur Section: 8 cm; Périmètre de la Section: 30.5 cm; Développement de la Section: 0 cm; Surface de la Section: 0 cm2; Surface: 4900 cm2; Volume: 0 cm3
IFC_Pset_Matériaux - Principal: Aluminium mat
Pset_BuildingElementProxyCommon - Reference: Base [P02] 80x80mm (..\Base\)
Group: ...de matériaux et couleurs = Aluminium mat; ...de profils et formes = Base [P02] 80x80mm
Name | __RECOGNIZE__, ID = IFC_Pset_Caractéristiques, ID | 0, DocType | 0, Tag | 0, Crc | 1, DocType | 1, Tag | 1, Crc | Numérotation
Extrusion (solide) 448653 | 448653 | 5 | -10 | 402591002 | 2 | 0 | 913068333 | 03
Extrusion (solide) 449444 | 449444 | 2 | 0 | 913068333 | 5 | -10 | 402591002 | 06
Extrusion (solide) 449482 | 449482 | 2 | 0 | 913068333 | 5 | -10 | 402591002 | 10
Extrusion (solide) 449459 | 449459 | 2 | 0 | 913068333 | 5 | -10 | 402591002 | 08

# IfcBuildingElementProxy: Base [R] 200x30mm, Extrusion (solide) 394737
In: Rez-de-chaussée
Type - Material: Aluminium mat
__RECOGNIZE__ - ID: 394737; TPLG: 273; TPLG_OD: 273; GENERATE: 1
CTLG_EXTERNAL_LINK - 0, DocType: 5; 0, Tag: -10; 0, Crc: -1527624253; 1, DocType: 2; 1, Tag: 0; 1, Crc: 913068333
IFC_PSET_PolygonOffset - polygonOffsetFactor: 2; polygonOffsetUnits: 2
IFC_Pset_Caractéristiques_Profil - Profil: Base [R] 200x30mm; Rotation: 180; Symétrie: no
IFC_Pset_Caractéristiques - Décalage: [0,00; 0,00] mm; ID: 394737; Numérotation: 02; Numéro niveau: 03; Titre niveau: Rez-de-chaussée
IFC_Pset_Géométrie - Fermé: no
IFC_Pset_Système de Référence Altimétrique_INFÉRIEUR - NIVEAU: Rez-de-chaussée (Rez-de-chaussée 1047); delta: 0 cm; sous Niveau: <aucun>
IFC_Pset_Données Métré - Longueur (totale): 193.7 cm; Largeur section: 20 cm; Hauteur Section: 3 cm; Périmètre de la Section: 46 cm; Développement de la Section: 0 cm; Surface de la Section: 100 cm2; Surface: 8900 cm2; Volume: 20000 cm3
IFC_Pset_Matériaux - Principal: Aluminium mat
Pset_BuildingElementProxyCommon - Reference: Base [R] 200x30mm (..\Base\)
Group: ...de matériaux et couleurs = Aluminium mat; ...de profils et formes = Base [R] 200x30mm

# IfcBuildingElementProxy: Base arrondi (13)
In: Mezzanine
Type - Material: Aluminium mat
__RECOGNIZE__ - TPLG: 273; TPLG_OD: 273; GENERATE: 1
IFC_PSET_PolygonOffset - polygonOffsetFactor: 2; polygonOffsetUnits: 2
IFC_Pset_Caractéristiques_Profil - Profil: Base arrondi; Symétrie: no
IFC_Pset_Caractéristiques - Décalage: [0,00; 0,00] mm; Numéro niveau: 06; Titre niveau: Mezzanine
IFC_Pset_Géométrie - Fermé: no
IFC_Pset_Système de Référence Altimétrique_INFÉRIEUR - NIVEAU: Mezzanine (Mezzanine 49003); sous Niveau: <aucun>
IFC_Pset_Données Métré - Largeur section: 3.4 cm; Hauteur Section: 4 cm; Périmètre de la Section: 13.1 cm; Développement de la Section: 0 cm; Surface de la Section: 0 cm2; Volume: 0 cm3
IFC_Pset_Matériaux - Principal: Aluminium mat
Pset_BuildingElementProxyCommon - Reference: Base arrondi (..\Base\)
Group: ...de matériaux et couleurs = Aluminium mat; ...de profils et formes = Base arrondi
Name | __RECOGNIZE__, ID = IFC_Pset_Caractéristiques, ID | 0, DocType | 0, Tag | 0, Crc | 1, DocType | 1, Tag | 1, Crc | Rotation | Numérotation | delta (cm) | Longueur (totale) (cm) | Surface (cm2)
Extrusion (solide) 1547946 | 1547946 | 5 | -10 | -1893435083 | 2 | 0 | 913068333 | 180 | 66 | 0 | 172.2 | 2300
Extrusion (solide) 1548115 | 1548115 | 5 | -10 | -1893435083 | 2 | 0 | 913068333 | 0 | 78 | 0 | 1104.7 | 14500
Extrusion (solide) 1547951 | 1547951 | 2 | 0 | 913068333 | 5 | -10 | -1893435083 | 180 | 70 | 3 | 156.5 | 2100
Extrusion (solide) 1547952 | 1547952 | 2 | 0 | 913068333 | 5 | -10 | -1893435083 | 180 | 71 | 3 | 159.7 | 2100
Extrusion (solide) 1547950 | 1547950 | 2 | 0 | 913068333 | 5 | -10 | -1893435083 | 180 | 69 | 3 | 153.3 | 2000
Extrusion (solide) 1547947 | 1547947 | 5 | -10 | -1893435083 | 2 | 0 | 913068333 | 180 | 67 | 3 | 160.6 | 2100
Extrusion (solide) 1547949 | 1547949 | 2 | 0 | 913068333 | 5 | -10 | -1893435083 | 180 | 68 | 3 | 161.7 | 2100
Extrusion (solide) 1547953 | 1547953 | 2 | 0 | 913068333 | 5 | -10 | -1893435083 | 180 | 72 | 3 | 160.2 | 2100
Extrusion (solide) 1547957 | 1547957 | 2 | 0 | 913068333 | 5 | -10 | -1893435083 | 180 | 76 | 0 | 138.1 | 1800
Extrusion (solide) 1548114 | 1548114 | 5 | -10 | -1893435083 | 2 | 0 | 913068333 | 0 | 77 | 0 | 962.6 | 12600
Extrusion (solide) 1547956 | 1547956 | 5 | -10 | -1893435083 | 2 | 0 | 913068333 | 180 | 75 | 0 | 144.1 | 1900
Extrusion (solide) 1547954 | 1547954 | 2 | 0 | 913068333 | 5 | -10 | -1893435083 | 180 | 73 | 3 | 172.1 | 2300
Extrusion (solide) 1547955 | 1547955 | 2 | 0 | 913068333 | 5 | -10 | -1893435083 | 180 | 74 | 3 | 158.6 | 2100

# IfcBuildingElementProxy: Base100x80mm, Extrusion (solide) 380567
In: Rez-de-Jardin
Type - Material: Aluminium mat
__RECOGNIZE__ - ID: 380567; TPLG: 273; TPLG_OD: 273; GENERATE: 1
CTLG_EXTERNAL_LINK - 0, DocType: 5; 0, Tag: -10; 0, Crc: 1544883754; 1, DocType: 2; 1, Tag: 0; 1, Crc: 913068333
IFC_PSET_PolygonOffset - polygonOffsetFactor: 2; polygonOffsetUnits: 2
IFC_Pset_Caractéristiques_Profil - Profil: Base100x80mm; Rotation: 90; Symétrie: no
IFC_Pset_Caractéristiques - Décalage: [0,00; 0,00] mm; ID: 380567; Numérotation: 01; Numéro niveau: 02; Titre niveau: Rez-de-Jardin
IFC_Pset_Géométrie - Fermé: no
IFC_Pset_Système de Référence Altimétrique_INFÉRIEUR - NIVEAU: Rez-de-Jardin (Rez-de-Jardin 15545); delta: 281.4 cm; sous Niveau: <aucun>
IFC_Pset_Données Métré - Longueur (totale): 1144.4 cm; Largeur section: 10 cm; Hauteur Section: 8 cm; Périmètre de la Section: 34.1 cm; Développement de la Section: 0 cm; Surface de la Section: 100 cm2; Surface: 39000 cm2; Volume: 110000 cm3
IFC_Pset_Matériaux - Principal: Aluminium mat
Pset_BuildingElementProxyCommon - Reference: Base100x80mm (..\Base\)
Group: ...de matériaux et couleurs = Aluminium mat; ...de profils et formes = Base100x80mm

# IfcBuildingElementProxy: Chaudière à condensation - Ariston - Clas B Premium Evo, Bloc 3D 78031
In: Rez-de-Jardin
Type - Material: Transparent, Logo_Ariston, Blanc, Blanc pur, Noir profond, Bleu clair, Gris béton
__RECOGNIZE__ - ID: 78031; TPLG: 820; TPLG_OD: 820; GENERATE: 1
CTLG_EXTERNAL_LINK - 0, DocType: 12; 0, Tag: 2; 0, Crc: -611642506; 1, DocType: 2; 1, Tag: 100; 1, Crc: -623492449; 2, DocType: 2; 2, Tag: 101; 2, Crc: 608536532; 3, DocType: 2; 3, Tag: 102; 3, Crc: 889432042; 4, DocType: 2; 4, Tag: 103; 4, Crc: 262804626; 5, DocType: 2; 5, Tag: 104; 5, Crc: -214186658; 6, DocType: 2; 6, Tag: 105; 6, Crc: -724316745; 7, DocType: 2; 7, Tag: 106; 7, Crc: -1697816127
IFC_PSET_PolygonOffset - polygonOffsetFactor: 2; polygonOffsetUnits: 2
IFC_Pset_Caractéristiques - ID: 78031; Numérotation: 01; Numéro niveau: 02; Titre niveau: Rez-de-Jardin; Modèle: Chaudière à condensation - Ariston - Clas B Premium Evo
IFC_Pset_Système de Référence Altimétrique_INFÉRIEUR - NIVEAU: Rez-de-Jardin (Rez-de-Jardin 15545); delta: 33 cm; sous Niveau: <aucun>
Pset_BuildingElementProxyCommon - Reference: Chaudière à condensation - Ariston - Clas B Premium Evo (..\Equipements\Chaudières\)
Group: ...de matériaux et couleurs - 1 = Blanc; ...de blocs 3d = Chaudière à condensation - Ariston - Clas B Premium Evo; ...de matériaux et couleurs = Transparent; ...de matériaux et couleurs - 2 = Noir profond; ...de matériaux et couleurs - 3 = Gris béton; ...de matériaux et couleurs - 4 = Bleu clair; ...de matériaux et couleurs - 5 = Logo_Ariston; ...de matériaux et couleurs - 6 = Blanc pur

# IfcBuildingElementProxy: Corniche extérieure [P01] 150x150mm (10)
Type - Material: Aluminium mat
__RECOGNIZE__ - TPLG: 273; TPLG_OD: 273; GENERATE: 1
IFC_PSET_PolygonOffset - polygonOffsetFactor: 2; polygonOffsetUnits: 2
IFC_Pset_Caractéristiques_Profil - Profil: Corniche extérieure [P01] 150x150mm; Symétrie: no
IFC_Pset_Caractéristiques - Décalage: [0,00; 0,00] mm; Numéro niveau: 06; Titre niveau: Mezzanine
IFC_Pset_Géométrie - Fermé: no
IFC_Pset_Système de Référence Altimétrique_INFÉRIEUR - NIVEAU: Mezzanine (Mezzanine 49003); sous Niveau: <aucun>
IFC_Pset_Données Métré - Largeur section: 10.9 cm; Hauteur Section: 7.8 cm; Périmètre de la Section: 34.3 cm; Développement de la Section: 0 cm; Surface de la Section: 0 cm2; Volume: 0 cm3
IFC_Pset_Matériaux - Principal: Aluminium mat
Pset_BuildingElementProxyCommon - Reference: Corniche extérieure [P01] 150x150mm (..\Corniche extérieure\)
Group: ...de matériaux et couleurs = Aluminium mat; ...de profils et formes = Corniche extérieure [P01] 150x150mm
Name | In | __RECOGNIZE__, ID = IFC_Pset_Caractéristiques, ID | 0, DocType | 0, Tag | 0, Crc | 1, DocType | 1, Tag | 1, Crc | Rotation | Numérotation | delta (cm) | Longueur (totale) (cm) | Surface (cm2)
Extrusion (solide) 996616 | Default Site | 996616 | 5 | -10 | 1660609951 | 2 | 0 | 913068333 | 0 | 54 | 0 | 249.2 | 8500
Extrusion (solide) 1015991 | Mezzanine | 1015991 | 2 | 0 | 913068333 | 5 | -10 | 1660609951 | 0 | 59 | 50 | 438.2 | 15000
Extrusion (solide) 1018724 | Mezzanine | 1018724 | 5 | -10 | 1660609951 | 2 | 0 | 913068333 | 0 | 60 | 0 | 248.2 | 8500
Extrusion (solide) 1015087 | Mezzanine | 1015087 | 5 | -10 | 1660609951 | 2 | 0 | 913068333 | 0 | 58 | 100 | 424.4 | 14600
Extrusion (solide) 1012988 | Mezzanine | 1012988 | 5 | -10 | 1660609951 | 2 | 0 | 913068333 | 0 | 56 | 0 | 248.2 | 8500
Extrusion (solide) 1013999 | Mezzanine | 1013999 | 5 | -10 | 1660609951 | 2 | 0 | 913068333 | 0 | 57 | 0 | 248.8 | 8500
Extrusion (solide) 1018901 | Mezzanine | 1018901 | 2 | 0 | 913068333 | 5 | -10 | 1660609951 | 0 | 61 | 0 | 413.5 | 14200
Extrusion (solide) 1149556 | Mezzanine | 1149556 | 5 | -10 | 1660609951 | 2 | 0 | 913068333 | 8.53774e-07 | 62 | 50 | 438.2 | 15000
Extrusion (solide) 1152841 | Mezzanine | 1152841 | 5 | -10 | 1660609951 | 2 | 0 | 913068333 | 0 | 63 | 0 | 416.1 | 14300
Extrusion (solide) 1005745 | Mezzanine | 1005745 | 2 | 0 | 913068333 | 5 | -10 | 1660609951 | 0 | 55 | 0 | 249.6 | 8600

# IfcBuildingElementProxy: Corniche niv1 (27)
Type - Material: Aluminium mat
__RECOGNIZE__ - TPLG: 273; TPLG_OD: 273; GENERATE: 1
IFC_PSET_PolygonOffset - polygonOffsetFactor: 2; polygonOffsetUnits: 2
IFC_Pset_Caractéristiques_Profil - Profil: Corniche niv1; Rotation: 180; Symétrie: no
IFC_Pset_Caractéristiques - Décalage: [0,00; 0,00] mm
IFC_Pset_Géométrie - Fermé: no
IFC_Pset_Système de Référence Altimétrique_INFÉRIEUR - sous Niveau: <aucun>
IFC_Pset_Données Métré - Largeur section: 10 cm; Hauteur Section: 21.4 cm; Périmètre de la Section: 68.7 cm; Développement de la Section: 0 cm; Surface de la Section: 100 cm2
IFC_Pset_Matériaux - Principal: Aluminium mat
Pset_BuildingElementProxyCommon - Reference: Corniche niv1 (..\Corniche\)
Group: ...de matériaux et couleurs = Aluminium mat; ...de profils et formes = Corniche niv1
Name | In | __RECOGNIZE__, ID = IFC_Pset_Caractéristiques, ID | 0, DocType | 0, Tag | 0, Crc | 1, DocType | 1, Tag | 1, Crc | Numérotation | Numéro niveau | Titre niveau | NIVEAU | delta (cm) | Longueur (totale) (cm) | Surface (cm2) | Volume (cm3)
Extrusion (solide) 956349 | Rez-de-chaussée | 956349 | 5 | -10 | 1866209590 | 2 | 0 | 913068333 | 37 | 03 | Rez-de-chaussée | Rez-de-chaussée (Rez-de-chaussée 1047) | 443 | 195 | 13400 | 20000
Extrusion (solide) 956350 | Rez-de-chaussée | 956350 | 5 | -10 | 1866209590 | 2 | 0 | 913068333 | 38 | 03 | Rez-de-chaussée | Rez-de-chaussée (Rez-de-chaussée 1047) | 442.5 | 45.1 | 3100 | 0
Extrusion (solide) 956348 | Rez-de-chaussée | 956348 | 5 | -10 | 1866209590 | 2 | 0 | 913068333 | 36 | 03 | Rez-de-chaussée | Rez-de-chaussée (Rez-de-chaussée 1047) | 443 | 330.6 | 22700 | 30000
Extrusion (solide) 956346 | Rez-de-chaussée | 956346 | 5 | -10 | 1866209590 | 2 | 0 | 913068333 | 34 | 03 | Rez-de-chaussée | Rez-de-chaussée (Rez-de-chaussée 1047) | 442 | 873.3 | 60000 | 90000
Extrusion (solide) 956347 | Rez-de-chaussée | 956347 | 5 | -10 | 1866209590 | 2 | 0 | 913068333 | 35 | 03 | Rez-de-chaussée | Rez-de-chaussée (Rez-de-chaussée 1047) | 442 | 1173.5 | 80600 | 120000
Extrusion (solide) 954635 | Rez-de-chaussée | 954635 | 5 | -10 | 1866209590 | 2 | 0 | 913068333 | 26 | 03 | Rez-de-chaussée | Rez-de-chaussée (Rez-de-chaussée 1047) | 443 | 358.9 | 24700 | 40000
Extrusion (solide) 954636 | Rez-de-chaussée | 954636 | 5 | -10 | 1866209590 | 2 | 0 | 913068333 | 27 | 03 | Rez-de-chaussée | Rez-de-chaussée (Rez-de-chaussée 1047) | 443 | 493.8 | 33900 | 50000
Extrusion (solide) 954634 | Rez-de-chaussée | 954634 | 5 | -10 | 1866209590 | 2 | 0 | 913068333 | 25 | 03 | Rez-de-chaussée | Rez-de-chaussée (Rez-de-chaussée 1047) | 443 | 876.6 | 60200 | 90000
Extrusion (solide) 954633 | Rez-de-chaussée | 954633 | 5 | -10 | 1866209590 | 2 | 0 | 913068333 | 24 | 03 | Rez-de-chaussée | Rez-de-chaussée (Rez-de-chaussée 1047) | 279 | 832.4 | 57200 | 80000
Extrusion (solide) 954637 | Rez-de-chaussée | 954637 | 5 | -10 | 1866209590 | 2 | 0 | 913068333 | 28 | 03 | Rez-de-chaussée | Rez-de-chaussée (Rez-de-chaussée 1047) | 443 | 229.2 | 15700 | 20000
Extrusion (solide) 956344 | Rez-de-chaussée | 956344 | 5 | -10 | 1866209590 | 2 | 0 | 913068333 | 32 | 03 | Rez-de-chaussée | Rez-de-chaussée (Rez-de-chaussée 1047) | 442 | 328.2 | 22500 | 30000
Extrusion (solide) 956345 | Rez-de-chaussée | 956345 | 5 | -10 | 1866209590 | 2 | 0 | 913068333 | 33 | 03 | Rez-de-chaussée | Rez-de-chaussée (Rez-de-chaussée 1047) | 441 | 875.7 | 60200 | 90000
Extrusion (solide) 956343 | Rez-de-chaussée | 956343 | 5 | -10 | 1866209590 | 2 | 0 | 913068333 | 31 | 03 | Rez-de-chaussée | Rez-de-chaussée (Rez-de-chaussée 1047) | 443 | 328.2 | 22500 | 30000
Extrusion (solide) 954638 | Rez-de-chaussée | 954638 | 5 | -10 | 1866209590 | 2 | 0 | 913068333 | 29 | 03 | Rez-de-chaussée | Rez-de-chaussée (Rez-de-chaussée 1047) | 442.5 | 276 | 19000 | 30000
Extrusion (solide) 954639 | Rez-de-chaussée | 954639 | 5 | -10 | 1866209590 | 2 | 0 | 913068333 | 30 | 03 | Rez-de-chaussée | Rez-de-chaussée (Rez-de-chaussée 1047) | 442.5 | 326.5 | 22400 | 30000
Extrusion (solide) 449946 | Niveau 1 | 449946 | 5 | -10 | 1866209590 | 2 | 0 | 913068333 | 15 | 04 | Niveau 1 | Niveau 1 (Niveau 1 2343) | 341 | 281.1 | 19300 | 30000
Extrusion (solide) 449947 | Niveau 1 | 449947 | 5 | -10 | 1866209590 | 2 | 0 | 913068333 | 16 | 04 | Niveau 1 | Niveau 1 (Niveau 1 2343) | 342 | 899.1 | 61800 | 90000
Extrusion (solide) 449945 | Niveau 1 | 449945 | 2 | 0 | 913068333 | 5 | -10 | 1866209590 | 14 | 04 | Niveau 1 | Niveau 1 (Niveau 1 2343) | 343 | 224.2 | 15400 | 20000
Extrusion (solide) 449943 | Niveau 1 | 449943 | 5 | -10 | 1866209590 | 2 | 0 | 913068333 | 12 | 04 | Niveau 1 | Niveau 1 (Niveau 1 2343) | 365 | 833.6 | 57300 | 80000
Extrusion (solide) 449944 | Niveau 1 | 449944 | 5 | -10 | 1866209590 | 2 | 0 | 913068333 | 13 | 04 | Niveau 1 | Niveau 1 (Niveau 1 2343) | 344 | 861.5 | 59200 | 90000
Extrusion (solide) 449948 | Niveau 1 | 449948 | 5 | -10 | 1866209590 | 2 | 0 | 913068333 | 17 | 04 | Niveau 1 | Niveau 1 (Niveau 1 2343) | 342 | 327.1 | 22500 | 30000
Extrusion (solide) 449952 | Niveau 1 | 449952 | 5 | -10 | 1866209590 | 2 | 0 | 913068333 | 21 | 04 | Niveau 1 | Niveau 1 (Niveau 1 2343) | 343 | 328.6 | 22600 | 30000
Extrusion (solide) 449953 | Niveau 1 | 449953 | 5 | -10 | 1866209590 | 2 | 0 | 913068333 | 22 | 04 | Niveau 1 | Niveau 1 (Niveau 1 2343) | 1163 | 177 | 12200 | 20000
Extrusion (solide) 449951 | Niveau 1 | 449951 | 5 | -10 | 1866209590 | 2 | 0 | 913068333 | 20 | 04 | Niveau 1 | Niveau 1 (Niveau 1 2343) | 343 | 1173.3 | 80600 | 120000
Extrusion (solide) 449949 | Niveau 1 | 449949 | 5 | -10 | 1866209590 | 2 | 0 | 913068333 | 18 | 04 | Niveau 1 | Niveau 1 (Niveau 1 2343) | 342 | 875.7 | 60200 | 90000
Extrusion (solide) 449950 | Niveau 1 | 449950 | 5 | -10 | 1866209590 | 2 | 0 | 913068333 | 19 | 04 | Niveau 1 | Niveau 1 (Niveau 1 2343) | 343 | 869.9 | 59800 | 90000
Extrusion (solide) 956351 | Niveau 1 | 956351 | 5 | -10 | 1866209590 | 2 | 0 | 913068333 | 39 | 04 | Niveau 1 | Niveau 1 (Niveau 1 2343) | 365 | 42.1 | 2900 | 0

# IfcBuildingElementProxy: Corniche niv2 (11)
In: Niveau 2
Type - Material: Aluminium mat
__RECOGNIZE__ - TPLG: 273; TPLG_OD: 273; GENERATE: 1
CTLG_EXTERNAL_LINK - 0, DocType: 5; 0, Tag: -10; 0, Crc: 1616195089; 1, DocType: 2; 1, Tag: 0; 1, Crc: 913068333
IFC_PSET_PolygonOffset - polygonOffsetFactor: 2; polygonOffsetUnits: 2
IFC_Pset_Caractéristiques_Profil - Profil: Corniche niv2; Rotation: 0; Symétrie: no
IFC_Pset_Caractéristiques - Décalage: [0,00; 0,00] mm; Numéro niveau: 05; Titre niveau: Niveau 2
IFC_Pset_Géométrie - Fermé: no
IFC_Pset_Système de Référence Altimétrique_INFÉRIEUR - NIVEAU: Niveau 2 (Niveau 2 13545); sous Niveau: <aucun>
IFC_Pset_Données Métré - Largeur section: 22.8 cm; Hauteur Section: 47.9 cm; Périmètre de la Section: 135.7 cm; Développement de la Section: 0 cm; Surface de la Section: 300 cm2
IFC_Pset_Matériaux - Principal: Aluminium mat
Pset_BuildingElementProxyCommon - Reference: Corniche niv2 (..\Corniche\)
Group: ...de matériaux et couleurs = Aluminium mat; ...de profils et formes = Corniche niv2
Name | __RECOGNIZE__, ID = IFC_Pset_Caractéristiques, ID | Numérotation | delta (cm) | Longueur (totale) (cm) | Surface (cm2) | Volume (cm3)
Extrusion (solide) 956360 | 956360 | 48 | 217.5 | 395.3 | 53600 | 120000
Extrusion (solide) 956361 | 956361 | 49 | 217.5 | 626.4 | 85000 | 190000
Extrusion (solide) 956359 | 956359 | 47 | 216 | 1740.2 | 236100 | 520000
Extrusion (solide) 956357 | 956357 | 45 | 219 | 501.1 | 68000 | 150000
Extrusion (solide) 956358 | 956358 | 46 | 216 | 259.9 | 35300 | 80000
Extrusion (solide) 956362 | 956362 | 50 | 217.5 | 832.3 | 112900 | 250000
Extrusion (solide) 956355 | 956355 | 43 | 220 | 835.5 | 113400 | 250000
Extrusion (solide) 956356 | 956356 | 44 | 216 | 761.2 | 103300 | 230000
Extrusion (solide) 956354 | 956354 | 42 | 217 | 582.9 | 79100 | 170000
Extrusion (solide) 956352 | 956352 | 40 | 24 | 358 | 48600 | 110000
Extrusion (solide) 956353 | 956353 | 41 | 217 | 302.3 | 41000 | 90000

# IfcBuildingElementProxy: Couvertine niv1, Extrusion (solide) 954630
In: Niveau 2
Type - Material: Aluminium mat
__RECOGNIZE__ - ID: 954630; TPLG: 273; TPLG_OD: 273; GENERATE: 1
CTLG_EXTERNAL_LINK - 0, DocType: 5; 0, Tag: -10; 0, Crc: 1461373384; 1, DocType: 2; 1, Tag: 0; 1, Crc: 913068333
IFC_PSET_PolygonOffset - polygonOffsetFactor: 2; polygonOffsetUnits: 2
IFC_Pset_Caractéristiques_Profil - Profil: Couvertine niv1; Rotation: 0; Symétrie: no
IFC_Pset_Caractéristiques - Décalage: [0,00; 0,00] mm; ID: 954630; Numérotation: 23; Numéro niveau: 05; Titre niveau: Niveau 2
IFC_Pset_Géométrie - Fermé: no
IFC_Pset_Système de Référence Altimétrique_INFÉRIEUR - NIVEAU: Niveau 2 (Niveau 2 13545); delta: 30 cm; sous Niveau: <aucun>
IFC_Pset_Données Métré - Longueur (totale): 897.2 cm; Largeur section: 63.7 cm; Hauteur Section: 27.4 cm; Périmètre de la Section: 169.4 cm; Développement de la Section: 0 cm; Surface de la Section: 1500 cm2; Surface: 152000 cm2; Volume: 1350000 cm3
IFC_Pset_Matériaux - Principal: Aluminium mat
Pset_BuildingElementProxyCommon - Reference: Couvertine niv1 (..\Bordure\)
Group: ...de matériaux et couleurs = Aluminium mat; ...de profils et formes = Couvertine niv1

# IfcBuildingElementProxy: Couvre-mur [P02] 300mm (5)
In: Niveau 1
Type - Material: Aluminium mat
__RECOGNIZE__ - TPLG: 273; TPLG_OD: 273; GENERATE: 1
IFC_PSET_PolygonOffset - polygonOffsetFactor: 2; polygonOffsetUnits: 2
IFC_Pset_Caractéristiques_Profil - Profil: Couvre-mur [P02] 300mm; Rotation: 0; Symétrie: no
IFC_Pset_Caractéristiques - Décalage: [0,00; 0,00] mm; Numéro niveau: 04; Titre niveau: Niveau 1
IFC_Pset_Géométrie - Fermé: no
IFC_Pset_Système de Référence Altimétrique_INFÉRIEUR - NIVEAU: Niveau 1 (Niveau 1 2343); delta: 83 cm; sous Niveau: <aucun>
IFC_Pset_Données Métré - Largeur section: 37.5 cm; Hauteur Section: 5.1 cm; Périmètre de la Section: 82.4 cm; Développement de la Section: 0 cm; Surface de la Section: 200 cm2; Volume: 30000 cm3
IFC_Pset_Matériaux - Principal: Aluminium mat
Pset_BuildingElementProxyCommon - Reference: Couvre-mur [P02] 300mm (..\Couvre-mur\)
Group: ...de matériaux et couleurs = Aluminium mat; ...de profils et formes = Couvre-mur [P02] 300mm
Name | __RECOGNIZE__, ID = IFC_Pset_Caractéristiques, ID | 0, DocType | 0, Tag | 0, Crc | 1, DocType | 1, Tag | 1, Crc | Numérotation | Longueur (totale) (cm) | Surface (cm2)
Extrusion (solide) 449433 | 449433 | 5 | -10 | -1517511767 | 2 | 0 | 913068333 | 04 | 158.1 | 13000
Extrusion (solide) 449434 | 449434 | 2 | 0 | 913068333 | 5 | -10 | -1517511767 | 05 | 159.7 | 13200
Extrusion (solide) 449488 | 449488 | 5 | -10 | -1517511767 | 2 | 0 | 913068333 | 11 | 159.7 | 13200
Extrusion (solide) 449465 | 449465 | 5 | -10 | -1517511767 | 2 | 0 | 913068333 | 09 | 159.7 | 13200
Extrusion (solide) 449450 | 449450 | 5 | -10 | -1517511767 | 2 | 0 | 913068333 | 07 | 159.7 | 13200

# IfcBuildingElementProxy: Défribillateur externe automatique - E010, Bloc 3D 959292
In: Rez-de-Jardin
Type - Material: Blanc signal, Vert signal
__RECOGNIZE__ - ID: 959292; TPLG: 820; TPLG_OD: 820; GENERATE: 1
CTLG_EXTERNAL_LINK - 0, DocType: 2; 0, Tag: 100; 0, Crc: -1359474068; 1, DocType: 2; 1, Tag: 101; 1, Crc: -2072708670; 2, DocType: 12; 2, Tag: 2; 2, Crc: -8619249
IFC_PSET_PolygonOffset - polygonOffsetFactor: 2; polygonOffsetUnits: 2
IFC_Pset_Caractéristiques - ID: 959292; Numérotation: 51; Numéro niveau: 02; Titre niveau: Rez-de-Jardin; Modèle: Défribillateur externe automatique - E010
IFC_Pset_Système de Référence Altimétrique_INFÉRIEUR - NIVEAU: Rez-de-Jardin (Rez-de-Jardin 15545); delta: 250 cm; sous Niveau: <aucun>
Pset_BuildingElementProxyCommon - Reference: Défribillateur externe automatique - E010 (..\CHANTIER\Signalisation\Signaux de sécurité - ISO 7010\)
Group: ...de matériaux et couleurs = Blanc signal; ...de matériaux et couleurs - 1 = Vert signal; ...de blocs 3d = Défribillateur externe automatique - E010

# IfcBuildingElementProxy: Lampe à mur - Hobbyka - Pushkin (2)
In: Rez-de-Jardin
Type - Material: Transparent, Olive gris
__RECOGNIZE__ - TPLG: 820; TPLG_OD: 820; GENERATE: 1
CTLG_EXTERNAL_LINK - 0, DocType: 2; 0, Tag: 100; 0, Crc: -444474409; 1, DocType: 2; 1, Tag: 101; 1, Crc: -623492449; 2, DocType: 12; 2, Tag: 2; 2, Crc: -1492387232
IFC_PSET_PolygonOffset - polygonOffsetFactor: 2; polygonOffsetUnits: 2
IFC_Pset_Caractéristiques - Numéro niveau: 02; Titre niveau: Rez-de-Jardin; Modèle: Lampe à mur - Hobbyka - Pushkin
IFC_Pset_Système de Référence Altimétrique_INFÉRIEUR - NIVEAU: Rez-de-Jardin (Rez-de-Jardin 15545); sous Niveau: extérieur
Pset_BuildingElementProxyCommon - Reference: Lampe à mur - Hobbyka - Pushkin (..\Illumination extérieure\Lampe à parois\)
Group: ...de matériaux et couleurs = Olive gris; ...de matériaux et couleurs - 1 = Transparent; ...de blocs 3d = Lampe à mur - Hobbyka - Pushkin
Name | __RECOGNIZE__, ID = IFC_Pset_Caractéristiques, ID | Numérotation | delta (cm)
Bloc 3D 294728 | 294728 | 35 | 240
Bloc 3D 294727 | 294727 | 34 | 262

# IfcBuildingElementProxy: Poubelle - Glänta - Skala - 267266 (3)
In: Rez-de-Jardin
Type - Material: Acier, Épicéa
__RECOGNIZE__ - TPLG: 820; TPLG_OD: 820; GENERATE: 1
CTLG_EXTERNAL_LINK - 0, DocType: 2; 0, Tag: 100; 0, Crc: -459882616; 1, DocType: 2; 1, Tag: 101; 1, Crc: -1206998685; 2, DocType: 12; 2, Tag: 2; 2, Crc: 1051821995
IFC_PSET_PolygonOffset - polygonOffsetFactor: 2; polygonOffsetUnits: 2
IFC_Pset_Caractéristiques - Numéro niveau: 02; Titre niveau: Rez-de-Jardin; Modèle: Poubelle - Glänta - Skala - 267266
IFC_Pset_Système de Référence Altimétrique_INFÉRIEUR - NIVEAU: Rez-de-Jardin (Rez-de-Jardin 15545); sous Niveau: <aucun>
Pset_BuildingElementProxyCommon - Reference: Poubelle - Glänta - Skala - 267266 (..\Aménagement urbain\Accessoires\)
Group: ...de matériaux et couleurs = Épicéa; ...de matériaux et couleurs - 1 = Acier; ...de blocs 3d = Poubelle - Glänta - Skala - 267266
Name | __RECOGNIZE__, ID = IFC_Pset_Caractéristiques, ID | Numérotation | delta (cm)
Bloc 3D 294729 | 294729 | 36 | 120
Bloc 3D 294981 | 294981 | 38 | 120
Bloc 3D 303644 | 303644 | 46 | 115

# IfcBuildingElementProxy: Profil [C] Ø35mm (10)
In: Rez-de-chaussée
Type - Material: Aluminium mat
__RECOGNIZE__ - TPLG: 273; TPLG_OD: 273; GENERATE: 1
IFC_PSET_PolygonOffset - polygonOffsetFactor: 2; polygonOffsetUnits: 2
IFC_Pset_Caractéristiques_Profil - Profil: Profil [C] Ø35mm; Rotation: 0; Symétrie: no
IFC_Pset_Caractéristiques - Décalage: [0,00; 0,00] mm; Numéro niveau: 03; Titre niveau: Rez-de-chaussée
IFC_Pset_Géométrie - Fermé: no
IFC_Pset_Système de Référence Altimétrique_INFÉRIEUR - NIVEAU: Rez-de-chaussée (Rez-de-chaussée 1047); sous Niveau: <aucun>
IFC_Pset_Données Métré - Longueur (totale): 124.6 cm; Largeur section: 3.5 cm; Hauteur Section: 3.5 cm; Périmètre de la Section: 11 cm; Développement de la Section: 0 cm; Surface de la Section: 0 cm2; Surface: 1400 cm2; Volume: 0 cm3
IFC_Pset_Matériaux - Principal: Aluminium mat
Pset_BuildingElementProxyCommon - Reference: Profil [C] Ø35mm (..\Profil circulaire\)
Group: ...de matériaux et couleurs = Aluminium mat; ...de profils et formes = Profil [C] Ø35mm
Name | __RECOGNIZE__, ID = IFC_Pset_Caractéristiques, ID | 0, DocType | 0, Tag | 0, Crc | 1, DocType | 1, Tag | 1, Crc | Numérotation | delta (cm)
Extrusion (solide) 1702445 | 1702445 | 5 | -10 | -684854450 | 2 | 0 | 913068333 | 81 | 368
Extrusion (solide) 1702446 | 1702446 | 5 | -10 | -684854450 | 2 | 0 | 913068333 | 82 | 438
Extrusion (solide) 1702444 | 1702444 | 2 | 0 | 913068333 | 5 | -10 | -684854450 | 80 | 312
Extrusion (solide) 1702443 | 1702443 | 5 | -10 | -684854450 | 2 | 0 | 913068333 | 79 | 300
Extrusion (solide) 1702447 | 1702447 | 5 | -10 | -684854450 | 2 | 0 | 913068333 | 83 | 450
Extrusion (solide) 1702452 | 1702452 | 2 | 0 | 913068333 | 5 | -10 | -684854450 | 87 | 438
Extrusion (solide) 1702453 | 1702453 | 2 | 0 | 913068333 | 5 | -10 | -684854450 | 88 | 450
Extrusion (solide) 1702451 | 1702451 | 2 | 0 | 913068333 | 5 | -10 | -684854450 | 86 | 368
Extrusion (solide) 1702448 | 1702448 | 2 | 0 | 913068333 | 5 | -10 | -684854450 | 84 | 300
Extrusion (solide) 1702450 | 1702450 | 5 | -10 | -684854450 | 2 | 0 | 913068333 | 85 | 312

# IfcBuildingElementProxy: Profil projet_1, Extrusion (solide) 975130
In: Mezzanine
Type - Material: Aluminium mat
__RECOGNIZE__ - ID: 975130; TPLG: 273; TPLG_OD: 273; GENERATE: 1
CTLG_EXTERNAL_LINK - 0, DocType: 5; 0, Tag: -10; 0, Crc: -1768708482; 1, DocType: 2; 1, Tag: 0; 1, Crc: 913068333
IFC_PSET_PolygonOffset - polygonOffsetFactor: 2; polygonOffsetUnits: 2
IFC_Pset_Caractéristiques_Profil - Profil: Profil projet_1; Rotation: 0; Symétrie: no
IFC_Pset_Caractéristiques - Décalage: [0,00; 0,00] mm; ID: 975130; Numérotation: 51; Numéro niveau: 06; Titre niveau: Mezzanine
IFC_Pset_Géométrie - Fermé: no
IFC_Pset_Système de Référence Altimétrique_INFÉRIEUR - NIVEAU: Mezzanine (Mezzanine 49003); delta: 0 cm; sous Niveau: <aucun>
IFC_Pset_Données Métré - Longueur (totale): 2076.2 cm; Largeur section: 8 cm; Hauteur Section: 13 cm; Périmètre de la Section: 42 cm; Développement de la Section: 0 cm; Surface de la Section: 100 cm2; Surface: 87200 cm2; Volume: 210000 cm3
IFC_Pset_Matériaux - Principal: Aluminium mat
Pset_BuildingElementProxyCommon - Reference: Profil projet_1 (..\Profil rectangulaire\)
Group: ...de matériaux et couleurs = Aluminium mat; ...de profils et formes = Profil projet_1

# IfcBuildingElementProxy: Radiateur en acier - Senia Group - Agatha (9)
In: Niveau 2
Type - Material: Blanc pur, Chrome poli
__RECOGNIZE__ - TPLG: 820; TPLG_OD: 820; GENERATE: 1
CTLG_EXTERNAL_LINK - 1, DocType: 2
IFC_PSET_PolygonOffset - polygonOffsetFactor: 2; polygonOffsetUnits: 2
IFC_Pset_Caractéristiques - Numéro niveau: 05; Titre niveau: Niveau 2; Modèle: Radiateur en acier - Senia Group - Agatha
IFC_Pset_Système de Référence Altimétrique_INFÉRIEUR - NIVEAU: Niveau 2 (Niveau 2 13545); delta: 20 cm; sous Niveau: <aucun>
Pset_BuildingElementProxyCommon - Reference: Radiateur en acier - Senia Group - Agatha (..\Equipements\Radiateur et Ventilateur-convecteur\)
Name | __RECOGNIZE__, ID = IFC_Pset_Caractéristiques, ID | 0, DocType | 0, Tag | 0, Crc | 1, Tag | 1, Crc | 2, DocType | 2, Tag | 2, Crc | Numérotation | Group
Bloc 3D 166957 | 166957 | 12 | 2 | -1154303517 | 100 | 609341495 | 2 | 101 | 39353375 | 30 | ...de blocs 3d = Radiateur en acier - Senia Group - Agatha; ...de matériaux et couleurs = Blanc pur; ...de matériaux et couleurs - 1 = Chrome poli
Bloc 3D 163739 | 163739 | 2 | 100 | 609341495 | 101 | 39353375 | 12 | 2 | -1154303517 | 29 | ...de blocs 3d = Radiateur en acier - Senia Group - Agatha; ...de matériaux et couleurs = Blanc pur; ...de matériaux et couleurs - 1 = Chrome poli
Bloc 3D 177163 | 177163 | 12 | 2 | -1154303517 | 100 | 609341495 | 2 | 101 | 39353375 | 31 | ...de blocs 3d = Radiateur en acier - Senia Group - Agatha; ...de matériaux et couleurs = Blanc pur; ...de matériaux et couleurs - 1 = Chrome poli
Bloc 3D 2052965 | 2052965 | 2 | 100 | 609341495 | 101 | 39353375 | 12 | 2 | -1154303517 | 53 | ...de blocs 3d = Radiateur en acier - Senia Group - Agatha; ...de matériaux et couleurs = Blanc pur; ...de matériaux et couleurs - 1 = Chrome poli
Bloc 3D 1719964 | 1719964 | 2 | 100 | 609341495 | 101 | 39353375 | 2 | 102 | -1637103103 | 52 | ...de matériaux et couleurs - 2 = Sapin blanc; ...de blocs 3d = Radiateur en acier - Senia Group - Agatha; ...de matériaux et couleurs = Blanc pur; ...de matériaux et couleurs - 1 = Chrome poli | CTLG_EXTERNAL_LINK - 3, DocType: 12; 3, Tag: 2; 3, Crc: -1154303517
Bloc 3D 158944 | 158944 | 2 | 100 | 609341495 | 101 | 39353375 | 12 | 2 | -1154303517 | 27 | ...de blocs 3d = Radiateur en acier - Senia Group - Agatha; ...de matériaux et couleurs = Blanc pur; ...de matériaux et couleurs - 1 = Chrome poli
Bloc 3D 158765 | 158765 | 2 | 100 | 609341495 | 101 | 39353375 | 12 | 2 | -1154303517 | 26 | ...de blocs 3d = Radiateur en acier - Senia Group - Agatha; ...de matériaux et couleurs = Blanc pur; ...de matériaux et couleurs - 1 = Chrome poli
Bloc 3D 152972 | 152972 | 2 | 100 | 609341495 | 101 | 39353375 | 12 | 2 | -1154303517 | 25 | ...de blocs 3d = Radiateur en acier - Senia Group - Agatha; ...de matériaux et couleurs = Blanc pur; ...de matériaux et couleurs - 1 = Chrome poli
Bloc 3D 152934 | 152934 | 12 | 2 | -1154303517 | 100 | 609341495 | 2 | 101 | 39353375 | 24 | ...de blocs 3d = Radiateur en acier - Senia Group - Agatha; ...de matériaux et couleurs = Blanc pur; ...de matériaux et couleurs - 1 = Chrome poli

# IfcBuildingElementProxy: Radiateur en acier - Senia Group - Alaska (25)
Type - Material: Chrome poli, Blanc, Blanc pur
__RECOGNIZE__ - TPLG: 820; TPLG_OD: 820; GENERATE: 1
CTLG_EXTERNAL_LINK - 1, DocType: 2; 2, DocType: 2
IFC_PSET_PolygonOffset - polygonOffsetFactor: 2; polygonOffsetUnits: 2
IFC_Pset_Caractéristiques - Modèle: Radiateur en acier - Senia Group - Alaska
IFC_Pset_Système de Référence Altimétrique_INFÉRIEUR - sous Niveau: <aucun>
Pset_BuildingElementProxyCommon - Reference: Radiateur en acier - Senia Group - Alaska (..\Equipements\Radiateur et Ventilateur-convecteur\)
Group: ...de matériaux et couleurs - 2 = Blanc; ...de matériaux et couleurs = Blanc pur; ...de matériaux et couleurs - 1 = Chrome poli; ...de blocs 3d = Radiateur en acier - Senia Group - Alaska
Name | In | __RECOGNIZE__, ID = IFC_Pset_Caractéristiques, ID | 0, DocType | 0, Tag | 0, Crc | 1, Tag | 1, Crc | 2, Tag | 2, Crc | 3, DocType | 3, Tag | 3, Crc | Numérotation | Numéro niveau | Titre niveau | NIVEAU | delta (cm)
Bloc 3D 78759 | Rez-de-Jardin | 78759 | 12 | 2 | 895001336 | 100 | -1697816127 | 101 | 39353375 | 2 | 102 | 1549567909 | 10 | 02 | Rez-de-Jardin | Rez-de-Jardin (Rez-de-Jardin 15545) | 0
Bloc 3D 78756 | Rez-de-Jardin | 78756 | 2 | 100 | -1697816127 | 101 | 39353375 | 102 | 1549567909 | 12 | 2 | -2027946317 | 09 | 02 | Rez-de-Jardin | Rez-de-Jardin (Rez-de-Jardin 15545) | 0
Bloc 3D 78755 | Rez-de-Jardin | 78755 | 2 | 100 | -1697816127 | 101 | 39353375 | 102 | 1549567909 | 12 | 2 | 895001336 | 08 | 02 | Rez-de-Jardin | Rez-de-Jardin (Rez-de-Jardin 15545) | 0
Bloc 3D 78760 | Rez-de-Jardin | 78760 | 2 | 100 | -1697816127 | 101 | 39353375 | 102 | 1549567909 | 12 | 2 | 895001336 | 11 | 02 | Rez-de-Jardin | Rez-de-Jardin (Rez-de-Jardin 15545) | 0
Bloc 3D 78754 | Rez-de-Jardin | 78754 | 2 | 100 | -1697816127 | 101 | 39353375 | 102 | 1549567909 | 12 | 2 | -1835239116 | 07 | 02 | Rez-de-Jardin | Rez-de-Jardin (Rez-de-Jardin 15545) | 0
Bloc 3D 78750 | Rez-de-Jardin | 78750 | 2 | 100 | -1697816127 | 101 | 39353375 | 102 | 1549567909 | 12 | 2 | 895001336 | 03 | 02 | Rez-de-Jardin | Rez-de-Jardin (Rez-de-Jardin 15545) | 20
Bloc 3D 78749 | Rez-de-Jardin | 78749 | 2 | 100 | -1697816127 | 101 | 39353375 | 102 | 1549567909 | 12 | 2 | -2027946317 | 02 | 02 | Rez-de-Jardin | Rez-de-Jardin (Rez-de-Jardin 15545) | 0
Bloc 3D 78753 | Rez-de-Jardin | 78753 | 2 | 100 | -1697816127 | 101 | 39353375 | 102 | 1549567909 | 12 | 2 | -1835239116 | 06 | 02 | Rez-de-Jardin | Rez-de-Jardin (Rez-de-Jardin 15545) | 0
Bloc 3D 78752 | Rez-de-Jardin | 78752 | 12 | 2 | 895001336 | 100 | -1697816127 | 101 | 39353375 | 2 | 102 | 1549567909 | 05 | 02 | Rez-de-Jardin | Rez-de-Jardin (Rez-de-Jardin 15545) | 0
Bloc 3D 78751 | Rez-de-Jardin | 78751 | 2 | 100 | -1697816127 | 101 | 39353375 | 102 | 1549567909 | 12 | 2 | -1835239116 | 04 | 02 | Rez-de-Jardin | Rez-de-Jardin (Rez-de-Jardin 15545) | 0
Bloc 3D 103651 | Niveau 1 | 103651 | 2 | 100 | -1697816127 | 101 | 39353375 | 102 | 1549567909 | 12 | 2 | -1835239116 | 13 | 04 | Niveau 1 | Niveau 1 (Niveau 1 2343) | 20
Bloc 3D 94967 | Niveau 1 | 94967 | 2 | 100 | -1697816127 | 101 | 39353375 | 102 | 1549567909 | 12 | 2 | -2027946317 | 12 | 04 | Niveau 1 | Niveau 1 (Niveau 1 2343) | 120
Bloc 3D 133234 | Niveau 1 | 133234 | 12 | 2 | -2027946317 | 100 | -1697816127 | 101 | 39353375 | 2 | 102 | 1549567909 | 21 | 04 | Niveau 1 | Niveau 1 (Niveau 1 2343) | 120
Bloc 3D 128666 | Niveau 1 | 128666 | 12 | 2 | -1835239116 | 100 | -1697816127 | 101 | 39353375 | 2 | 102 | 1549567909 | 20 | 04 | Niveau 1 | Niveau 1 (Niveau 1 2343) | 20
Bloc 3D 118807 | Niveau 1 | 118807 | 2 | 100 | -1697816127 | 101 | 39353375 | 102 | 1549567909 | 12 | 2 | -2027946317 | 16 | 04 | Niveau 1 | Niveau 1 (Niveau 1 2343) | 120
Bloc 3D 115413 | Niveau 1 | 115413 | 12 | 2 | -2027946317 | 100 | -1697816127 | 101 | 39353375 | 2 | 102 | 1549567909 | 15 | 04 | Niveau 1 | Niveau 1 (Niveau 1 2343) | 120
Bloc 3D 103654 | Niveau 1 | 103654 | 12 | 2 | -1835239116 | 100 | -1697816127 | 101 | 39353375 | 2 | 102 | 1549567909 | 14 | 04 | Niveau 1 | Niveau 1 (Niveau 1 2343) | 20
Bloc 3D 128664 | Niveau 1 | 128664 | 2 | 100 | -1697816127 | 101 | 39353375 | 102 | 1549567909 | 12 | 2 | -1835239116 | 19 | 04 | Niveau 1 | Niveau 1 (Niveau 1 2343) | 20
Bloc 3D 121284 | Niveau 1 | 121284 | 2 | 100 | -1697816127 | 101 | 39353375 | 102 | 1549567909 | 12 | 2 | -1835239116 | 18 | 04 | Niveau 1 | Niveau 1 (Niveau 1 2343) | 20
Bloc 3D 121129 | Niveau 1 | 121129 | 2 | 100 | -1697816127 | 101 | 39353375 | 102 | 1549567909 | 12 | 2 | -1835239116 | 17 | 04 | Niveau 1 | Niveau 1 (Niveau 1 2343) | 20
Bloc 3D 159510 | Niveau 2 | 159510 | 2 | 100 | -1697816127 | 101 | 39353375 | 102 | 1549567909 | 12 | 2 | -2027946317 | 28 | 05 | Niveau 2 | Niveau 2 (Niveau 2 13545) | 35
Bloc 3D 152385 | Niveau 2 | 152385 | 2 | 100 | -1697816127 | 101 | 39353375 | 102 | 1549567909 | 12 | 2 | -2027946317 | 23 | 05 | Niveau 2 | Niveau 2 (Niveau 2 13545) | 35
Bloc 3D 151083 | Niveau 2 | 151083 | 2 | 100 | -1697816127 | 101 | 39353375 | 102 | 1549567909 | 12 | 2 | -2027946317 | 22 | 05 | Niveau 2 | Niveau 2 (Niveau 2 13545) | 35
Bloc 3D 198194 | Mezzanine | 198194 | 12 | 2 | -2027946317 | 100 | -1697816127 | 101 | 39353375 | 2 | 102 | 1549567909 | 33 | 06 | Mezzanine | Mezzanine (Mezzanine 49003) | 75
Bloc 3D 192847 | Mezzanine | 192847 | 2 | 100 | -1697816127 | 101 | 39353375 | 102 | 1549567909 | 12 | 2 | -2027946317 | 32 | 06 | Mezzanine | Mezzanine (Mezzanine 49003) | 75

# IfcBuildingElementProxy: Range-vélos deux places - Cyklos - Delta - 314106, Bloc 3D 294971
In: Rez-de-Jardin
Type - Material: Gris aluminium, Bleu clair
__RECOGNIZE__ - ID: 294971; TPLG: 820; TPLG_OD: 820; GENERATE: 1
CTLG_EXTERNAL_LINK - 0, DocType: 12; 0, Tag: 2; 0, Crc: -661835735; 1, DocType: 2; 1, Tag: 100; 1, Crc: -214186658; 2, DocType: 2; 2, Tag: 101; 2, Crc: -1611473673
IFC_PSET_PolygonOffset - polygonOffsetFactor: 2; polygonOffsetUnits: 2
IFC_Pset_Caractéristiques - ID: 294971; Numérotation: 37; Numéro niveau: 02; Titre niveau: Rez-de-Jardin; Modèle: Range-vélos deux places - Cyklos - Delta - 314106
IFC_Pset_Système de Référence Altimétrique_INFÉRIEUR - NIVEAU: Rez-de-Jardin (Rez-de-Jardin 15545); delta: 105.595 cm; sous Niveau: <aucun>
Pset_BuildingElementProxyCommon - Reference: Range-vélos deux places - Cyklos - Delta - 314106 (..\Aménagement urbain\Accessoires\)
Group: ...de blocs 3d = Range-vélos deux places - Cyklos - Delta - 314106; ...de matériaux et couleurs = Bleu clair; ...de matériaux et couleurs - 1 = Gris aluminium

# IfcBuildingElementProxy: Retombé Corniche_1 (2)
In: Mezzanine
Type - Material: Aluminium mat
__RECOGNIZE__ - TPLG: 273; TPLG_OD: 273; GENERATE: 1
CTLG_EXTERNAL_LINK - 0, DocType: 5; 0, Tag: -10; 0, Crc: 1711259101; 1, DocType: 2; 1, Tag: 0; 1, Crc: 913068333
IFC_PSET_PolygonOffset - polygonOffsetFactor: 2; polygonOffsetUnits: 2
IFC_Pset_Caractéristiques_Profil - Profil: Retombé Corniche_1; Symétrie: no
IFC_Pset_Caractéristiques - Décalage: [0,00; 0,00] mm; Numéro niveau: 06; Titre niveau: Mezzanine
IFC_Pset_Géométrie - Fermé: no
IFC_Pset_Système de Référence Altimétrique_INFÉRIEUR - NIVEAU: Mezzanine (Mezzanine 49003); sous Niveau: <aucun>
IFC_Pset_Données Métré - Largeur section: 31 cm; Hauteur Section: 101.3 cm; Périmètre de la Section: 244 cm; Développement de la Section: 0 cm; Surface de la Section: 2400 cm2; Volume: 80000 cm3
IFC_Pset_Matériaux - Principal: Aluminium mat
Pset_BuildingElementProxyCommon - Reference: Retombé Corniche_1 (..\Corniche d'étage\)
Group: ...de matériaux et couleurs = Aluminium mat; ...de profils et formes = Retombé Corniche_1
Name | __RECOGNIZE__, ID = IFC_Pset_Caractéristiques, ID | Rotation | Numérotation | delta (cm) | Longueur (totale) (cm) | Surface (cm2)
Extrusion (solide) 975132 | 975132 | 0 | 53 | -30 | 33 | 8100
Extrusion (solide) 975131 | 975131 | 360 | 52 | -150 | 32.7 | 8000

# IfcBuildingElementProxy: Réverbère sur poteau de hauteur 3,5m - iGuzzini - Crown simmetrico (7)
In: Rez-de-Jardin
Type - Material: Transparent, Gris lumière
__RECOGNIZE__ - TPLG: 820; TPLG_OD: 820; GENERATE: 1
CTLG_EXTERNAL_LINK - 1, DocType: 2
IFC_PSET_PolygonOffset - polygonOffsetFactor: 2; polygonOffsetUnits: 2
IFC_Pset_Caractéristiques - Numéro niveau: 02; Titre niveau: Rez-de-Jardin; Modèle: Réverbère sur poteau de hauteur 3,5m - iGuzzini - Crown simmetrico
IFC_Pset_Système de Référence Altimétrique_INFÉRIEUR - NIVEAU: Rez-de-Jardin (Rez-de-Jardin 15545); delta: 110.988 cm; sous Niveau: <aucun>
Pset_BuildingElementProxyCommon - Reference: Réverbère sur poteau de hauteur 3,5m - iGuzzini - Crown simmetrico (..\Illumination extérieure\Réverbères routiers\)
Group: ...de matériaux et couleurs = Gris lumière; ...de matériaux et couleurs - 1 = Transparent; ...de blocs 3d = Réverbère sur poteau de hauteur 3,5m - iGuzzini - Crown simmetrico
Name | __RECOGNIZE__, ID = IFC_Pset_Caractéristiques, ID | 0, DocType | 0, Tag | 0, Crc | 1, Tag | 1, Crc | 2, DocType | 2, Tag | 2, Crc | Numérotation
Bloc 3D 303636 | 303636 | 12 | 2 | -887529304 | 100 | 1908701706 | 2 | 101 | -623492449 | 40
Bloc 3D 303656 | 303656 | 12 | 2 | -887529304 | 100 | 1908701706 | 2 | 101 | -623492449 | 47
Bloc 3D 303640 | 303640 | 2 | 100 | 1908701706 | 101 | -623492449 | 12 | 2 | -887529304 | 43
Bloc 3D 303639 | 303639 | 2 | 100 | 1908701706 | 101 | -623492449 | 12 | 2 | -887529304 | 42
Bloc 3D 303637 | 303637 | 2 | 100 | 1908701706 | 101 | -623492449 | 12 | 2 | -887529304 | 41
Bloc 3D 303643 | 303643 | 2 | 100 | 1908701706 | 101 | -623492449 | 12 | 2 | -887529304 | 45
Bloc 3D 303641 | 303641 | 2 | 100 | 1908701706 | 101 | -623492449 | 12 | 2 | -887529304 | 44

# IfcBuildingElementProxy: Tableau électrique de chantier (3)
In: Rez-de-Jardin
Type - Material: Blanc gris, Gris fer, Rouge brillant, Bleu clair, Jaune signal, Blanc signal, Gris beige, Noir signal
__RECOGNIZE__ - TPLG: 820; TPLG_OD: 820; GENERATE: 1
CTLG_EXTERNAL_LINK - 1, DocType: 2; 2, DocType: 2; 3, DocType: 2; 4, DocType: 2; 5, DocType: 2; 6, DocType: 2; 7, DocType: 2
IFC_PSET_PolygonOffset - polygonOffsetFactor: 2; polygonOffsetUnits: 2
IFC_Pset_Caractéristiques - Numéro niveau: 02; Titre niveau: Rez-de-Jardin; Modèle: Tableau électrique de chantier
IFC_Pset_Système de Référence Altimétrique_INFÉRIEUR - NIVEAU: Rez-de-Jardin (Rez-de-Jardin 15545); sous Niveau: <aucun>
Pset_BuildingElementProxyCommon - Reference: Tableau électrique de chantier (..\CHANTIER\Équipement\)
Group: ...de matériaux et couleurs = Blanc gris; ...de matériaux et couleurs - 1 = Bleu clair; ...de matériaux et couleurs - 2 = Gris fer; ...de matériaux et couleurs - 3 = Rouge brillant; ...de matériaux et couleurs - 4 = Gris beige; ...de matériaux et couleurs - 5 = Noir signal; ...de matériaux et couleurs - 6 = Jaune signal; ...de matériaux et couleurs - 7 = Blanc signal; ...de blocs 3d = Tableau électrique de chantier
Name | __RECOGNIZE__, ID = IFC_Pset_Caractéristiques, ID | 0, DocType | 0, Tag | 0, Crc | 1, Tag | 1, Crc | 2, Tag | 2, Crc | 3, Tag | 3, Crc | 4, Tag | 4, Crc | 5, Tag | 5, Crc | 6, Tag | 6, Crc | 7, Tag | 7, Crc | 8, DocType | 8, Tag | 8, Crc | Numérotation | delta (cm)
Bloc 3D 363232 | 363232 | 2 | 100 | 1422992700 | 101 | 1302820008 | 102 | 1090031111 | 103 | -1031479310 | 104 | -1975389710 | 105 | 1191639554 | 106 | -42412794 | 107 | -1359474068 | 12 | 2 | -375549310 | 50 | 200
Bloc 3D 328786 | 328786 | 2 | 100 | 1422992700 | 101 | 1302820008 | 102 | 1090031111 | 103 | -1031479310 | 104 | -1975389710 | 105 | 1191639554 | 106 | -42412794 | 107 | -1359474068 | 12 | 2 | -375549310 | 49 | 170
Bloc 3D 328785 | 328785 | 12 | 2 | -375549310 | 100 | 1422992700 | 101 | 1302820008 | 102 | 1090031111 | 103 | -1031479310 | 104 | -1975389710 | 105 | 1191639554 | 106 | -42412794 | 2 | 107 | -1359474068 | 48 | 170

# IfcBuildingElementProxy: profil L bord arrondi (2)
In: Couverture
Type - Material: Aluminium mat
__RECOGNIZE__ - TPLG: 273; TPLG_OD: 273; GENERATE: 1
CTLG_EXTERNAL_LINK - 0, DocType: 5; 0, Tag: -10; 0, Crc: 548081384; 1, DocType: 2; 1, Tag: 0; 1, Crc: 913068333
IFC_PSET_PolygonOffset - polygonOffsetFactor: 2; polygonOffsetUnits: 2
IFC_Pset_Caractéristiques_Profil - Profil: profil L bord arrondi; Rotation: 0; Symétrie: no
IFC_Pset_Caractéristiques - Décalage: [0,00; 0,00] mm; Numéro niveau: 07; Titre niveau: Couverture
IFC_Pset_Géométrie - Fermé: no
IFC_Pset_Système de Référence Altimétrique_INFÉRIEUR - NIVEAU: Couverture (Couverture 2134); sous Niveau: <aucun>
IFC_Pset_Données Métré - Largeur section: 11.8 cm; Hauteur Section: 17.3 cm; Périmètre de la Section: 54.6 cm; Développement de la Section: 0 cm; Surface de la Section: 0 cm2; Volume: 0 cm3
IFC_Pset_Matériaux - Principal: Aluminium mat
Pset_BuildingElementProxyCommon - Reference: profil L bord arrondi (..\Corniche extérieure\)
Group: ...de matériaux et couleurs = Aluminium mat; ...de profils et formes = profil L bord arrondi
Name | __RECOGNIZE__, ID = IFC_Pset_Caractéristiques, ID | Numérotation | delta (cm) | Longueur (totale) (cm) | Surface (cm2)
Extrusion (solide) 1314531 | 1314531 | 65 | -460 | 1085.6 | 59300
Extrusion (solide) 1314530 | 1314530 | 64 | -436 | 179.4 | 9800

# IfcColumn: 150.0x150.0x25.0 (6)
In: Mezzanine
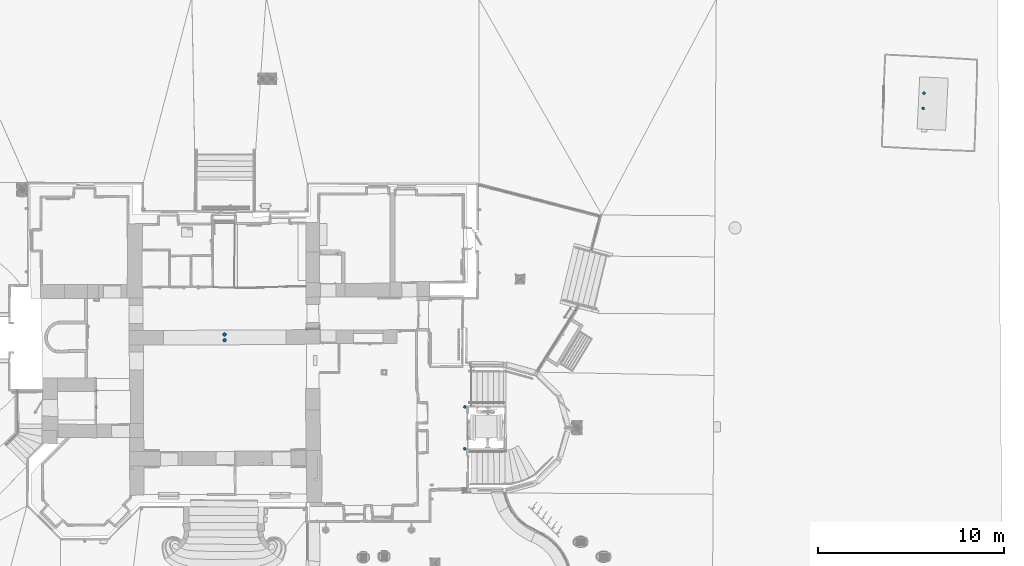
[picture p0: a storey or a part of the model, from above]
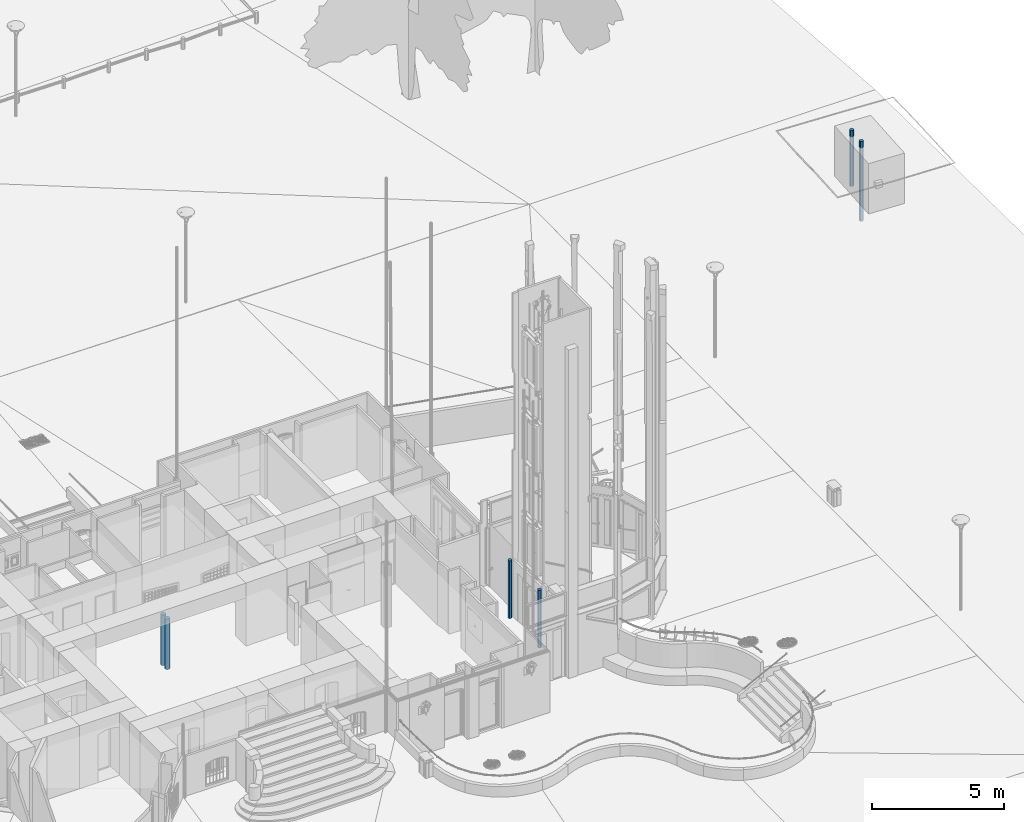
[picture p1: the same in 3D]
Properties of the parts of a building model (IFC2X3), part 4 of 37

# IfcColumn: 150.0x150.0x25.0 (6)
Type - PredefinedType: USERDEFINED; Material: Blanc
Description: Poteau; Group: ...de matériaux et couleurs = Blanc; ...de sections pour tiges = 150.0x150.0x25.0
__RECOGNIZE__ - TPLG: 200; TPLG_OD: 500; GENERATE: 1; Section_TypeForm: 0; Section, Section_NumItems: 1; Section, Section_Item 0, Section_ID: 124; Section, Section_Item 0, Section_Desc: 150x150; Section, Section_Item 0, Section_Categ: 3; Section, Section_Item 0, Section_Tipo: 22; Section, Section_Item 0, Section_Base: 0.15; Section, Section_Item 0, Section_H: 0.15; Section, Section_Item 0, Section_DistPrfX: 0; Section, Section_Item 0, Section_DistPrfY: 0; Section, Section_Item 0, Section_DispInPianta: 0; Section, Section_Item 0, Section_TipoForma: 0; Section, Section_Item 0, Section_AngleRot: 0; Section, Section_Item 0, Section_BrcX: 0; Section, Section_Item 0, Section_BrcY: 0
IFC_PSET_PolygonOffset - polygonOffsetFactor: 2; polygonOffsetUnits: 2
IFC_Pset_Alignment - Alignment_Sez: 0; Alignment_Poly: -1; Alignment_Nodo: -10; Alignment_TS: 0; Alignment_NODO_CLC: 0; Alignment_C_FC_SUP: 0
IFC_Pset_Caractéristiques - Numéro niveau: 06; Titre niveau: Mezzanine; Coupe: 150.0x150.0x25.0
IFC_Pset_Système de Référence Altimétrique_INFÉRIEUR - NIVEAU: Mezzanine; sous Niveau: <aucun>
IFC_Pset_Données Métré - Surface en Plan: 200 cm2; Base Section: 15 cm; Hauteur Section: 15 cm; Diamètre Section: 0 cm
IFC_Pset_Matériaux - Principal: Blanc
Pset_ColumnCommon - Reference: 150.0x150.0x25.0 (..\Section rectangulaire arrondie\); Slope: 90 deg
BaseQuantities - CrossSectionArea: 219.607 cm2
Name | __RECOGNIZE__, ID = IFC_Pset_Caractéristiques, ID | AngleRotaz | 0, DocType | 0, Tag | 0, Crc | 1, DocType | 1, Tag | 1, Crc | Numérotation | Hauteur (cm) = NominalLength (cm) | Rotation (deg) | Cote (cm) | NIVEAU | IFC_Pset_Système de Référence Altimétrique_SUPÉRIEUR, delta (cm) | sous Niveau | IFC_Pset_Système de Référence Altimétrique_INFÉRIEUR, delta (cm) | Surface (latérale) (cm2) | Volume (cm3) | OuterSurfaceArea (cm2) | TotalSurfaceArea (cm2) | GrossVolume (cm3) = NetVolume (cm3)
Poteau 834608 | 834608 | 0.816588 | 2 | 0 | -746779066 | 6 | -10 | -603927665 | 55 | 250.175 | 46.7871 | 0 | HAUT Mezzanine | -29.5277 | <aucun> | 0 | 13900 | 50000 | 13936.7 | 14375.9 | 54940.1
Poteau 1780557 | 1780557 | 0 | 2 | 0 | -746779066 | 6 | -10 | -603927665 | 65 | 214.702 | 0 | 0 | Couverture | -65 | <aucun> | 0 | 12000 | 40000 | 11960.6 | 12399.8 | 47150.2
Poteau 196101 | 196101 | 0 | 6 | -10 | -603927665 | 2 | 0 | -746779066 | 32 | 251.415 | 0 | 0 | Couverture | -28.2874 | Toit795368 | 0 | 14000 | 50000 | 14005.8 | 14445 | 55212.5
Poteau 197676 | 197676 | 0 | 6 | -10 | -603927665 | 2 | 0 | -746779066 | 34 | 52.3938 | 0 | 0 | Couverture | -227.309 | Toit793923 | 0 | 2900 | 10000 | 2918.75 | 3357.97 | 11506.1
Poteau 196095 | 196095 | 0 | 6 | -10 | -603927665 | 2 | 0 | -746779066 | 31 | 391.702 | 0 | 43 | HAUT Mezzanine | 155 | <aucun> | 232.716 | 21800 | 80000 | 21820.9 | 22260.2 | 86020.6
Poteau 197039 | 197039 | 1.54177 | 6 | -10 | -603927665 | 2 | 0 | -746779066 | 33 | 421.702 | 88.3368 | 48 | HAUT Mezzanine | 190 | <aucun> | 279.702 | 23500 | 80000 | 23492.2 | 23931.4 | 92608.8

# IfcColumn: 180x68 (5)
In: Mezzanine
Type - PredefinedType: USERDEFINED; Material: Blanc
Description: Poteau; Group: ...de matériaux et couleurs = Blanc; ...de sections pour tiges = 180x68
__RECOGNIZE__ - TPLG: 200; TPLG_OD: 500; GENERATE: 1; Section_TypeForm: 0; AngleRotaz: 4.70655; Section, Section_NumItems: 1; Section, Section_Item 0, Section_ID: 134; Section, Section_Item 0, Section_Desc: 68.00x180.00; Section, Section_Item 0, Section_Categ: 3; Section, Section_Item 0, Section_Tipo: 1; Section, Section_Item 0, Section_Base: 0.068; Section, Section_Item 0, Section_H: 0.18; Section, Section_Item 0, Section_DistPrfX: 0; Section, Section_Item 0, Section_DistPrfY: 0; Section, Section_Item 0, Section_DispInPianta: 0; Section, Section_Item 0, Section_TipoForma: 0; Section, Section_Item 0, Section_AngleRot: 0; Section, Section_Item 0, Section_BrcX: 0; Section, Section_Item 0, Section_BrcY: 0
CTLG_EXTERNAL_LINK - 0, DocType: 6; 0, Tag: -10; 0, Crc: 545790089; 1, DocType: 2; 1, Tag: 0; 1, Crc: -746779066
IFC_PSET_PolygonOffset - polygonOffsetFactor: 2; polygonOffsetUnits: 2
IFC_Pset_Alignment - Alignment_Sez: 0; Alignment_Poly: -1; Alignment_Nodo: -10; Alignment_TS: 0; Alignment_NODO_CLC: 0; Alignment_C_FC_SUP: 0
IFC_Pset_Caractéristiques - Numéro niveau: 06; Titre niveau: Mezzanine; Coupe: 180x68
IFC_Pset_Géométrie - Rotation: 269.666 deg
IFC_Pset_Géométrie_POINT inférieur - Cote: -18 cm
IFC_Pset_Système de Référence Altimétrique_INFÉRIEUR - NIVEAU: Mezzanine; sous Niveau: <aucun>
IFC_Pset_Données Métré - Surface en Plan: 0 cm2; Volume: 0 cm3; Base Section: 6.8 cm; Hauteur Section: 18 cm; Diamètre Section: 0 cm
IFC_Pset_Matériaux - Principal: Blanc
Pset_ColumnCommon - Reference: 180x68 (..\Section rectangulaire creuse\); Slope: 90 deg
BaseQuantities - CrossSectionArea: 9.76 cm2
Name | __RECOGNIZE__, ID = IFC_Pset_Caractéristiques, ID | Numérotation | Hauteur (cm) = NominalLength (cm) | NIVEAU | IFC_Pset_Système de Référence Altimétrique_SUPÉRIEUR, delta (cm) | sous Niveau | IFC_Pset_Système de Référence Altimétrique_INFÉRIEUR, delta (cm) | Surface (latérale) (cm2) | OuterSurfaceArea (cm2) | TotalSurfaceArea (cm2) | GrossVolume (cm3) = NetVolume (cm3)
Poteau 222993 | 222993 | 42 | 207.702 | HAUT Mezzanine | -90 | <aucun> | -18 | 10300 | 20271.8 | 20291.3 | 2027.18
Poteau 222994 | 222994 | 43 | 207.702 | HAUT Mezzanine | -90 | <aucun> | -18 | 10300 | 20271.8 | 20291.3 | 2027.18
Poteau 222999 | 222999 | 44 | 202.702 | HAUT Mezzanine | -95 | <aucun> | -18 | 10100 | 19783.8 | 19803.3 | 1978.38
Poteau 222987 | 222987 | 40 | 269.407 | Couverture | -28.2959 | Toit795368 | 212.307 | 13400 | 26294.1 | 26313.6 | 2629.41
Poteau 222984 | 222984 | 39 | 267.334 | Couverture | -30.368 | Toit795368 | 217.083 | 13300 | 26091.8 | 26111.4 | 2609.18

# IfcColumn: 200,00x200,00x10,00 (6)
In: Mezzanine
Type - PredefinedType: USERDEFINED; Material: Blanc
Description: Poteau; Group: ...de matériaux et couleurs = Blanc; ...de sections pour tiges = 200,00x200,00x10,00
__RECOGNIZE__ - TPLG: 200; TPLG_OD: 500; GENERATE: 1; Section_TypeForm: 0; Section, Section_NumItems: 1; Section, Section_Item 0, Section_ID: 118; Section, Section_Item 0, Section_Desc: 200,00x200,00x10,00; Section, Section_Item 0, Section_Categ: 3; Section, Section_Item 0, Section_Tipo: 22; Section, Section_Item 0, Section_Base: 0.2; Section, Section_Item 0, Section_H: 0.2; Section, Section_Item 0, Section_DistPrfX: 0; Section, Section_Item 0, Section_DistPrfY: 0; Section, Section_Item 0, Section_DispInPianta: 0; Section, Section_Item 0, Section_TipoForma: 0; Section, Section_Item 0, Section_AngleRot: 0; Section, Section_Item 0, Section_BrcX: 0; Section, Section_Item 0, Section_BrcY: 0
CTLG_EXTERNAL_LINK - 0, DocType: 6; 0, Tag: -10; 0, Crc: -579435193; 1, DocType: 2; 1, Tag: 0; 1, Crc: -746779066
IFC_PSET_PolygonOffset - polygonOffsetFactor: 2; polygonOffsetUnits: 2
IFC_Pset_Alignment - Alignment_Sez: 0; Alignment_Poly: -1; Alignment_Nodo: -10; Alignment_TS: 0; Alignment_NODO_CLC: 0; Alignment_C_FC_SUP: 0
IFC_Pset_Caractéristiques - Numéro niveau: 06; Titre niveau: Mezzanine; Coupe: 200,00x200,00x10,00
IFC_Pset_Système de Référence Altimétrique_INFÉRIEUR - NIVEAU: Mezzanine; sous Niveau: <aucun>
IFC_Pset_Données Métré - Surface en Plan: 400 cm2; Base Section: 20 cm; Hauteur Section: 20 cm; Diamètre Section: 0 cm
IFC_Pset_Matériaux - Principal: Blanc
Pset_ColumnCommon - Reference: 200,00x200,00x10,00 (..\Section rectangulaire arrondie\); Slope: 90 deg
BaseQuantities - CrossSectionArea: 399.138 cm2
Name | __RECOGNIZE__, ID = IFC_Pset_Caractéristiques, ID | AngleRotaz | Numérotation | Hauteur (cm) = NominalLength (cm) | Rotation (deg) | Cote (cm) | NIVEAU | IFC_Pset_Système de Référence Altimétrique_SUPÉRIEUR, delta (cm) | sous Niveau | IFC_Pset_Système de Référence Altimétrique_INFÉRIEUR, delta (cm) | Surface (latérale) (cm2) | Volume (cm3) | OuterSurfaceArea (cm2) | TotalSurfaceArea (cm2) | GrossVolume (cm3) = NetVolume (cm3)
Poteau 198254 | 198254 | 1.58037 | 36 | 231.702 | 90.5485 | 48 | HAUT Mezzanine | 0 | <aucun> | 48 | 18000 | 90000 | 17993.3 | 18791.6 | 92481.1
Poteau 222975 | 222975 | 0 | 37 | 207.349 | 0 | -18 | Couverture | -90.3533 | Toit795362 | -18 | 16100 | 80000 | 16102.1 | 16900.4 | 82760.8
Poteau 222978 | 222978 | 0 | 38 | 348 | 0 | -18 | HAUT Mezzanine | 50.2976 | <aucun> | 79.7024 | 27000 | 140000 | 27024.6 | 27822.9 | 138900
Poteau 222990 | 222990 | 0 | 41 | 297.702 | 0 | -18 | HAUT Mezzanine | 3.55271e-13 | <aucun> | 79.7024 | 23100 | 120000 | 23118.6 | 23916.9 | 118824
Poteau 192923 | 192923 | 0 | 30 | 340.702 | 0 | 94 | Couverture | 155 | <aucun> | 242.904 | 26500 | 140000 | 26457.9 | 27256.2 | 135987
Poteau 198086 | 198086 | 1.58037 | 35 | 421.702 | 90.5485 | 48 | HAUT Mezzanine | 190 | <aucun> | 191.926 | 32700 | 170000 | 32748.1 | 33546.4 | 168317

# IfcColumn: 2X1-5/16 (2)
In: Mezzanine
Type - PredefinedType: USERDEFINED; Material: Aluminium mat
Description: Poteau Acier; Group: ...de matériaux et couleurs = Aluminium mat; ...de profilés en acier = 2X1-5/16
__RECOGNIZE__ - TPLG: 202; TPLG_OD: 502; GENERATE: 1; Section_TypeForm: 0; AngleRotaz: 0; Section, Section_NumItems: 1; Section, Section_Item 0, Section_ID: 274; Section, Section_Item 0, Section_Desc: 4X2-5/16; Section, Section_Item 0, Section_Categ: 2; Section, Section_Item 0, Section_Tipo: 22; Section, Section_Item 0, Section_Base: 0.025; Section, Section_Item 0, Section_H: 0.05; Section, Section_Item 0, Section_DistPrfX: 0; Section, Section_Item 0, Section_DistPrfY: 0; Section, Section_Item 0, Section_DispInPianta: 0; Section, Section_Item 0, Section_TipoForma: 0; Section, Section_Item 0, Section_AngleRot: 0; Section, Section_Item 0, Section_BrcX: 0; Section, Section_Item 0, Section_BrcY: 0
CTLG_EXTERNAL_LINK - 0, DocType: 2; 0, Tag: 0; 0, Crc: 913068333; 1, DocType: 7; 1, Tag: -10; 1, Crc: 745588298
IFC_PSET_PolygonOffset - polygonOffsetFactor: 2; polygonOffsetUnits: 2
IFC_Pset_Alignment - Alignment_Sez: 0; Alignment_Poly: -1; Alignment_Nodo: -10; Alignment_TS: 0; Alignment_NODO_CLC: 0; Alignment_C_FC_SUP: 0
IFC_Pset_Caractéristiques - Numéro niveau: 06; Titre niveau: Mezzanine; Coupe: 2X1-5/16
IFC_Pset_Géométrie - Hauteur: 259.702 cm; Rotation: 0 deg
IFC_Pset_Géométrie_POINT inférieur - Cote: -235 cm
IFC_Pset_Système de Référence Altimétrique_SUPÉRIEUR - NIVEAU: HAUT Mezzanine; delta: -255 cm; sous Niveau: <aucun>
IFC_Pset_Système de Référence Altimétrique_INFÉRIEUR - NIVEAU: Mezzanine; delta: -110.298 cm; sous Niveau: <aucun>
IFC_Pset_Données Métré - Surface (latérale): 2000 cm2; Surface en Plan: 9.4 cm2; Volume: 1260 cm3; Base Section: 2.5 cm; Hauteur Section: 5 cm; Diamètre Section: 0 cm
IFC_Pset_Matériaux - Principal: Aluminium mat
Pset_ColumnCommon - Reference: 2X1-5/16 (..\Profilés\Rectangulaire vide arêtes vives\); Slope: 90 deg
BaseQuantities - NominalLength: 259.702 cm; CrossSectionArea: 9.3536 cm2; OuterSurfaceArea: 6149.75 cm2; TotalSurfaceArea: 6168.46 cm2; GrossVolume: 2429.15 cm3; NetVolume: 2429.15 cm3
Name | __RECOGNIZE__, ID = IFC_Pset_Caractéristiques, ID | Numérotation
Poteau Acier 1519593 | 1519593 | 13
Poteau Acier 1519596 | 1519596 | 14

# IfcColumn: O 244.5x6.3, Poteau Acier 197633
In: Mezzanine
Type - PredefinedType: USERDEFINED; Material: Aluminium mat
Description: Poteau Acier; Group: ...de matériaux et couleurs = Aluminium mat; ...de profilés en acier = O 244.5x6.3
__RECOGNIZE__ - ID: 197633; TPLG: 202; TPLG_OD: 502; GENERATE: 1; Section_TypeForm: 0; AngleRotaz: 0; Section, Section_NumItems: 1; Section, Section_Item 0, Section_ID: 208; Section, Section_Item 0, Section_Desc: O 244.5x6.3; Section, Section_Item 0, Section_Categ: 2; Section, Section_Item 0, Section_Tipo: 21; Section, Section_Item 0, Section_Base: 0.2445; Section, Section_Item 0, Section_H: 0.2445; Section, Section_Item 0, Section_DistPrfX: 0; Section, Section_Item 0, Section_DistPrfY: 0; Section, Section_Item 0, Section_DispInPianta: 0; Section, Section_Item 0, Section_TipoForma: 0; Section, Section_Item 0, Section_AngleRot: 0; Section, Section_Item 0, Section_BrcX: 0; Section, Section_Item 0, Section_BrcY: 0
CTLG_EXTERNAL_LINK - 0, DocType: 2; 0, Tag: 0; 0, Crc: 913068333; 1, DocType: 7; 1, Tag: -10; 1, Crc: 460484091
IFC_PSET_PolygonOffset - polygonOffsetFactor: 2; polygonOffsetUnits: 2
IFC_Pset_Alignment - Alignment_Sez: 0; Alignment_Poly: -1; Alignment_Nodo: -10; Alignment_TS: 0; Alignment_NODO_CLC: 0; Alignment_C_FC_SUP: 0
IFC_Pset_Caractéristiques - ID: 197633; Numérotation: 04; Numéro niveau: 06; Titre niveau: Mezzanine; Coupe: O 244.5x6.3
IFC_Pset_Géométrie - Hauteur: 79.7024 cm; Rotation: 0 deg
IFC_Pset_Géométrie_POINT inférieur - Cote: 100 cm
IFC_Pset_Système de Référence Altimétrique_SUPÉRIEUR - NIVEAU: HAUT Mezzanine; delta: -100 cm; sous Niveau: <aucun>
IFC_Pset_Système de Référence Altimétrique_INFÉRIEUR - NIVEAU: Mezzanine; delta: 100 cm; sous Niveau: <aucun>
IFC_Pset_Données Métré - Surface (latérale): 6100 cm2; Surface en Plan: 468.9 cm2; Volume: 37370 cm3; Base Section: 24.5 cm; Hauteur Section: 24.5 cm; Diamètre Section: 24.5 cm
IFC_Pset_Matériaux - Principal: Aluminium mat
Pset_ColumnCommon - Reference: O 244.5x6.3 (..\Profilés\Tubulaire\); Slope: 90 deg
BaseQuantities - NominalLength: 79.7024 cm; CrossSectionArea: 468.917 cm2; OuterSurfaceArea: 11928.7 cm2; TotalSurfaceArea: 12866.5 cm2; GrossVolume: 37373.8 cm3; NetVolume: 37373.8 cm3

# IfcColumn: O 273x5, Poteau Acier 197580
In: Mezzanine
Type - PredefinedType: USERDEFINED; Material: Aluminium mat
Description: Poteau Acier; Group: ...de matériaux et couleurs = Aluminium mat; ...de profilés en acier = O 273x5
__RECOGNIZE__ - ID: 197580; TPLG: 202; TPLG_OD: 502; GENERATE: 1; Section_TypeForm: 0; AngleRotaz: 0; Section, Section_NumItems: 1; Section, Section_Item 0, Section_ID: 192; Section, Section_Item 0, Section_Desc: O 273x5; Section, Section_Item 0, Section_Categ: 2; Section, Section_Item 0, Section_Tipo: 21; Section, Section_Item 0, Section_Base: 0.54; Section, Section_Item 0, Section_H: 0.54; Section, Section_Item 0, Section_DistPrfX: 0; Section, Section_Item 0, Section_DistPrfY: 0; Section, Section_Item 0, Section_DispInPianta: 0; Section, Section_Item 0, Section_TipoForma: 0; Section, Section_Item 0, Section_AngleRot: 0; Section, Section_Item 0, Section_BrcX: 0; Section, Section_Item 0, Section_BrcY: 0
CTLG_EXTERNAL_LINK - 0, DocType: 2; 0, Tag: 0; 0, Crc: 913068333; 1, DocType: 7; 1, Tag: -10; 1, Crc: -398212029
IFC_PSET_PolygonOffset - polygonOffsetFactor: 2; polygonOffsetUnits: 2
IFC_Pset_Alignment - Alignment_Sez: 0; Alignment_Poly: -1; Alignment_Nodo: -10; Alignment_TS: 0; Alignment_NODO_CLC: 0; Alignment_C_FC_SUP: 0
IFC_Pset_Caractéristiques - ID: 197580; Numérotation: 03; Numéro niveau: 06; Titre niveau: Mezzanine; Coupe: O 273x5
IFC_Pset_Géométrie - Hauteur: 73.7024 cm; Rotation: 0 deg
IFC_Pset_Géométrie_POINT inférieur - Cote: 70 cm
IFC_Pset_Système de Référence Altimétrique_SUPÉRIEUR - NIVEAU: HAUT Mezzanine; delta: -136 cm; sous Niveau: <aucun>
IFC_Pset_Système de Référence Altimétrique_INFÉRIEUR - NIVEAU: Mezzanine; delta: 70 cm; sous Niveau: <aucun>
IFC_Pset_Données Métré - Surface (latérale): 12500 cm2; Surface en Plan: 84.1 cm2; Volume: 6200 cm3; Base Section: 54 cm; Hauteur Section: 54 cm; Diamètre Section: 54 cm
IFC_Pset_Matériaux - Principal: Aluminium mat
Pset_ColumnCommon - Reference: O 273x5 (..\Profilés\Tubulaire\); Slope: 90 deg
BaseQuantities - NominalLength: 73.7024 cm; CrossSectionArea: 84.0931 cm2; OuterSurfaceArea: 24775.1 cm2; TotalSurfaceArea: 24943.3 cm2; GrossVolume: 6197.87 cm3; NetVolume: 6197.87 cm3

# IfcColumn: RND 160 (10)
Type - PredefinedType: USERDEFINED; Material: Aluminium mat
Description: Poteau Acier; Group: ...de matériaux et couleurs = Aluminium mat; ...de profilés en acier = RND 160
__RECOGNIZE__ - TPLG: 202; TPLG_OD: 502; GENERATE: 1; Section_TypeForm: 0; AngleRotaz: 0; Section, Section_NumItems: 1; Section, Section_Item 0, Section_ID: 224; Section, Section_Item 0, Section_Desc: RND 160; Section, Section_Item 0, Section_Categ: 2; Section, Section_Item 0, Section_Tipo: 23; Section, Section_Item 0, Section_Base: 0.16; Section, Section_Item 0, Section_H: 0.16; Section, Section_Item 0, Section_DistPrfX: 0; Section, Section_Item 0, Section_DistPrfY: 0; Section, Section_Item 0, Section_DispInPianta: 0; Section, Section_Item 0, Section_TipoForma: 0; Section, Section_Item 0, Section_AngleRot: 0; Section, Section_Item 0, Section_BrcX: 0; Section, Section_Item 0, Section_BrcY: 0
IFC_PSET_PolygonOffset - polygonOffsetFactor: 2; polygonOffsetUnits: 2
IFC_Pset_Alignment - Alignment_Sez: 0; Alignment_Poly: -1; Alignment_Nodo: -10; Alignment_TS: 0; Alignment_NODO_CLC: 0; Alignment_C_FC_SUP: 0
IFC_Pset_Caractéristiques - Coupe: RND 160
IFC_Pset_Géométrie - Rotation: 0 deg
IFC_Pset_Système de Référence Altimétrique_SUPÉRIEUR - sous Niveau: <aucun>
IFC_Pset_Système de Référence Altimétrique_INFÉRIEUR - sous Niveau: <aucun>
IFC_Pset_Données Métré - Surface en Plan: 200.8 cm2; Base Section: 16 cm; Hauteur Section: 16 cm; Diamètre Section: 16 cm
IFC_Pset_Matériaux - Principal: Aluminium mat
Pset_ColumnCommon - Reference: RND 160 (..\Profilés\Rond\); Slope: 90 deg
BaseQuantities - CrossSectionArea: 200.807 cm2
Name | In | __RECOGNIZE__, ID = IFC_Pset_Caractéristiques, ID | 0, DocType | 0, Tag | 0, Crc | 1, DocType | 1, Tag | 1, Crc | Numérotation | Numéro niveau | Titre niveau = IFC_Pset_Système de Référence Altimétrique_INFÉRIEUR, NIVEAU | Hauteur (cm) = NominalLength (cm) | Cote (cm) = IFC_Pset_Système de Référence Altimétrique_INFÉRIEUR, delta (cm) | IFC_Pset_Système de Référence Altimétrique_SUPÉRIEUR, NIVEAU | IFC_Pset_Système de Référence Altimétrique_SUPÉRIEUR, delta (cm) | Surface (latérale) (cm2) | Volume (cm3) | OuterSurfaceArea (cm2) | TotalSurfaceArea (cm2) | GrossVolume (cm3) = NetVolume (cm3)
Poteau Acier 1824237 | Rez-de-Jardin | 1824237 | 2 | 0 | 913068333 | 7 | -10 | -1510798125 | 21 | 02 | Rez-de-Jardin | 259.196 | 110 | HAUT Rez-de-chaussée | -400 | 13000 | 52050 | 13028.6 | 13430.2 | 52048.3
Poteau Acier 1824240 | Rez-de-Jardin | 1824240 | 2 | 0 | 913068333 | 7 | -10 | -1510798125 | 22 | 02 | Rez-de-Jardin | 369.196 | 0 | HAUT Rez-de-chaussée | -400 | 18600 | 74140 | 18557.8 | 18959.4 | 74137
Poteau Acier 574853 | Rez-de-Jardin | 574853 | 2 | 0 | 913068333 | 7 | -10 | -1510798125 | 05 | 02 | Rez-de-Jardin | 266.4 | 0 | HAUT Rez-de-Jardin | -25 | 13400 | 53500 | 13390.7 | 13792.4 | 53495
Poteau Acier 574856 | Rez-de-Jardin | 574856 | 2 | 0 | 913068333 | 7 | -10 | -1510798125 | 06 | 02 | Rez-de-Jardin | 266.4 | 0 | HAUT Rez-de-Jardin | -25 | 13400 | 53500 | 13390.7 | 13792.4 | 53495
Poteau Acier 705440 | Rez-de-chaussée | 705440 | 2 | 0 | 913068333 | 7 | -10 | -1510798125 | 07 | 03 | Rez-de-chaussée | 452.795 | 0 | HAUT Rez-de-chaussée | -25 | 22800 | 90920 | 22760 | 23161.6 | 90924.4
Poteau Acier 705443 | Rez-de-chaussée | 705443 | 2 | 0 | 913068333 | 7 | -10 | -1510798125 | 08 | 03 | Rez-de-chaussée | 452.795 | 0 | HAUT Rez-de-chaussée | -25 | 22800 | 90920 | 22760 | 23161.6 | 90924.4
Poteau Acier 718697 | Niveau 1 | 718697 | 7 | -10 | -1510798125 | 2 | 0 | 913068333 | 10 | 04 | Niveau 1 | 351.115 | 0 | HAUT Niveau 1 | -25 | 17600 | 70510 | 17649 | 18050.6 | 70506.3
Poteau Acier 718694 | Niveau 1 | 718694 | 7 | -10 | -1510798125 | 2 | 0 | 913068333 | 09 | 04 | Niveau 1 | 351.115 | 0 | HAUT Niveau 1 | -25 | 17600 | 70510 | 17649 | 18050.6 | 70506.3
Poteau Acier 724689 | Niveau 2 | 724689 | 2 | 0 | 913068333 | 7 | -10 | -1510798125 | 12 | 05 | Niveau 2 | 215 | 0 | HAUT Niveau 2 | -20 | 10800 | 43170 | 10807.1 | 11208.7 | 43173.5
Poteau Acier 724686 | Niveau 2 | 724686 | 2 | 0 | 913068333 | 7 | -10 | -1510798125 | 11 | 05 | Niveau 2 | 215 | 0 | HAUT Niveau 2 | -20 | 10800 | 43170 | 10807.1 | 11208.7 | 43173.5

# IfcColumn: RND 200 (2)
In: Rez-de-Jardin
Type - PredefinedType: USERDEFINED; Material: Bleu france
Description: Poteau Acier; Group: ...de matériaux et couleurs = Bleu france; ...de profilés en acier = RND 200
__RECOGNIZE__ - TPLG: 202; TPLG_OD: 502; GENERATE: 1; Section_TypeForm: 0; AngleRotaz: 0; Section, Section_NumItems: 1; Section, Section_Item 0, Section_ID: 190; Section, Section_Item 0, Section_Desc: RND 200; Section, Section_Item 0, Section_Categ: 2; Section, Section_Item 0, Section_Tipo: 23; Section, Section_Item 0, Section_Base: 0.2; Section, Section_Item 0, Section_H: 0.2; Section, Section_Item 0, Section_DistPrfX: 0; Section, Section_Item 0, Section_DistPrfY: 0; Section, Section_Item 0, Section_DispInPianta: 0; Section, Section_Item 0, Section_TipoForma: 0; Section, Section_Item 0, Section_AngleRot: 0; Section, Section_Item 0, Section_BrcX: 0; Section, Section_Item 0, Section_BrcY: 0
CTLG_EXTERNAL_LINK - 0, DocType: 2; 0, Tag: 0; 0, Crc: 1181025438; 1, DocType: 7; 1, Tag: -10; 1, Crc: -130512606
IFC_PSET_PolygonOffset - polygonOffsetFactor: 2; polygonOffsetUnits: 2
IFC_Pset_Alignment - Alignment_Sez: 0; Alignment_Poly: -1; Alignment_Nodo: -10; Alignment_TS: 0; Alignment_NODO_CLC: 0; Alignment_C_FC_SUP: 0
IFC_Pset_Caractéristiques - Numéro niveau: 02; Titre niveau: Rez-de-Jardin; Coupe: RND 200
IFC_Pset_Géométrie - Hauteur: 233.4 cm; Rotation: 0 deg
IFC_Pset_Géométrie_POINT inférieur - Cote: 0 cm
IFC_Pset_Système de Référence Altimétrique_SUPÉRIEUR - NIVEAU: HAUT Rez-de-Jardin; delta: -58 cm; sous Niveau: <aucun>
IFC_Pset_Système de Référence Altimétrique_INFÉRIEUR - NIVEAU: Rez-de-Jardin; delta: 0 cm; sous Niveau: <aucun>
IFC_Pset_Données Métré - Surface (latérale): 14700 cm2; Surface en Plan: 313.8 cm2; Volume: 73230 cm3; Base Section: 20 cm; Hauteur Section: 20 cm; Diamètre Section: 20 cm
IFC_Pset_Matériaux - Principal: Bleu france
Pset_ColumnCommon - Reference: RND 200 (..\Profilés\Rond\); Slope: 90 deg
BaseQuantities - NominalLength: 233.4 cm; CrossSectionArea: 313.761 cm2; OuterSurfaceArea: 14665 cm2; TotalSurfaceArea: 15292.5 cm2; GrossVolume: 73231.9 cm3; NetVolume: 73231.9 cm3
Name | __RECOGNIZE__, ID = IFC_Pset_Caractéristiques, ID | Numérotation
Poteau Acier 69972 | 69972 | 01
Poteau Acier 69975 | 69975 | 02

# IfcColumn: Ø140 (25)
In: Rez-de-Jardin
Type - PredefinedType: USERDEFINED; Material: Chêne rouvre 02
Description: Poteau; Group: ...de matériaux et couleurs = Chêne rouvre 02; ...de sections pour tiges = Ø140
__RECOGNIZE__ - TPLG: 200; TPLG_OD: 500; GENERATE: 1; Section_TypeForm: 0; AngleRotaz: 0; Section, Section_NumItems: 1; Section, Section_Item 0, Section_ID: 110; Section, Section_Item 0, Section_Desc: Ø140,00; Section, Section_Item 0, Section_Categ: 3; Section, Section_Item 0, Section_Tipo: 2; Section, Section_Item 0, Section_Base: 0.14; Section, Section_Item 0, Section_H: 0.14; Section, Section_Item 0, Section_DistPrfX: 0; Section, Section_Item 0, Section_DistPrfY: 0; Section, Section_Item 0, Section_DispInPianta: 0; Section, Section_Item 0, Section_TipoForma: 0; Section, Section_Item 0, Section_AngleRot: 0; Section, Section_Item 0, Section_BrcX: 0; Section, Section_Item 0, Section_BrcY: 0
CTLG_EXTERNAL_LINK - 0, DocType: 6; 0, Tag: -10; 0, Crc: -807232468; 1, DocType: 2; 1, Tag: 0; 1, Crc: -1439514055
IFC_PSET_PolygonOffset - polygonOffsetFactor: 2; polygonOffsetUnits: 2
IFC_Pset_Alignment - Alignment_Sez: 0; Alignment_Poly: -1; Alignment_Nodo: -10; Alignment_TS: 0; Alignment_NODO_CLC: 0; Alignment_C_FC_SUP: 0
IFC_Pset_Caractéristiques - Numéro niveau: 02; Titre niveau: Rez-de-Jardin; Coupe: Ø140
IFC_Pset_Géométrie - Rotation: 0 deg
IFC_Pset_Géométrie_POINT inférieur - Cote: 110 cm
IFC_Pset_Système de Référence Altimétrique_SUPÉRIEUR - NIVEAU: HAUT Rez-de-Jardin; sous Niveau: <aucun>
IFC_Pset_Système de Référence Altimétrique_INFÉRIEUR - NIVEAU: Rez-de-Jardin; delta: 110 cm; sous Niveau: extérieur
IFC_Pset_Données Métré - Surface en Plan: 200 cm2; Volume: 20000 cm3; Base Section: 14 cm; Hauteur Section: 14 cm; Diamètre Section: 14 cm
IFC_Pset_Matériaux - Principal: Chêne rouvre 02
Pset_ColumnCommon - Reference: Ø140 (..\Section circulaire\); Slope: 90 deg
BaseQuantities - CrossSectionArea: 153.743 cm2
Name | __RECOGNIZE__, ID = IFC_Pset_Caractéristiques, ID | Numérotation | Hauteur (cm) = NominalLength (cm) | delta (cm) | Surface (latérale) (cm2) | OuterSurfaceArea (cm2) | TotalSurfaceArea (cm2) | GrossVolume (cm3) = NetVolume (cm3)
Poteau 69572 | 69572 | 12 | 81.4004 | -150 | 3600 | 3580.18 | 3887.66 | 12514.7
Poteau 69573 | 69573 | 13 | 90.4004 | -141 | 4000 | 3976.02 | 4283.5 | 13898.4
Poteau 69570 | 69570 | 10 | 88.4004 | -143 | 3900 | 3888.05 | 4195.54 | 13590.9
Poteau 69574 | 69574 | 14 | 88.4004 | -143 | 3900 | 3888.05 | 4195.54 | 13590.9
Poteau 69577 | 69577 | 17 | 81.4004 | -150 | 3600 | 3580.18 | 3887.66 | 12514.7
Poteau 69578 | 69578 | 18 | 81.4004 | -150 | 3600 | 3580.18 | 3887.66 | 12514.7
Poteau 69576 | 69576 | 16 | 81.4004 | -150 | 3600 | 3580.18 | 3887.66 | 12514.7
Poteau 69563 | 69563 | 03 | 84.4004 | -147 | 3700 | 3712.12 | 4019.61 | 12975.9
Poteau 69564 | 69564 | 04 | 87.4004 | -144 | 3800 | 3844.07 | 4151.55 | 13437.2
Poteau 69561 | 69561 | 01 | 81.4004 | -150 | 3600 | 3580.18 | 3887.66 | 12514.7
Poteau 69562 | 69562 | 02 | 83.4004 | -148 | 3700 | 3668.14 | 3975.63 | 12822.2
Poteau 69565 | 69565 | 05 | 85.4004 | -146 | 3800 | 3756.1 | 4063.59 | 13129.7
Poteau 69568 | 69568 | 08 | 84.4004 | -147 | 3700 | 3712.12 | 4019.61 | 12975.9
Poteau 69569 | 69569 | 09 | 86.4004 | -145 | 3800 | 3800.09 | 4107.57 | 13283.4
Poteau 69566 | 69566 | 06 | 80.4004 | -151 | 3500 | 3536.19 | 3843.68 | 12361
Poteau 69567 | 69567 | 07 | 85.4004 | -146 | 3800 | 3756.1 | 4063.59 | 13129.7
Poteau 69579 | 69579 | 19 | 86.4004 | -145 | 3800 | 3800.09 | 4107.57 | 13283.4
Poteau 69590 | 69590 | 29 | 80.4004 | -151 | 3500 | 3536.19 | 3843.68 | 12361
Poteau 69583 | 69583 | 22 | 81.4004 | -150 | 3600 | 3580.18 | 3887.66 | 12514.7
Poteau 69584 | 69584 | 23 | 82.4004 | -149 | 3600 | 3624.16 | 3931.64 | 12668.5
Poteau 69580 | 69580 | 20 | 81.4004 | -150 | 3600 | 3580.18 | 3887.66 | 12514.7
Poteau 69582 | 69582 | 21 | 83.4004 | -148 | 3700 | 3668.14 | 3975.63 | 12822.2
Poteau 69588 | 69588 | 27 | 83.4004 | -148 | 3700 | 3668.14 | 3975.63 | 12822.2
Poteau 69589 | 69589 | 28 | 86.4004 | -145 | 3800 | 3800.09 | 4107.57 | 13283.4
Poteau 69587 | 69587 | 26 | 81.4004 | -150 | 3600 | 3580.18 | 3887.66 | 12514.7

# IfcColumn: Ø160 (13)
In: Rez-de-Jardin
Type - PredefinedType: USERDEFINED; Material: Chêne rouvre 02
Description: Poteau; Group: ...de matériaux et couleurs = Chêne rouvre 02; ...de sections pour tiges = Ø160
__RECOGNIZE__ - TPLG: 200; TPLG_OD: 500; GENERATE: 1; Section_TypeForm: 0; AngleRotaz: 0; Section, Section_NumItems: 1; Section, Section_Item 0, Section_ID: 108; Section, Section_Item 0, Section_Desc: Ø160,00; Section, Section_Item 0, Section_Categ: 3; Section, Section_Item 0, Section_Tipo: 2; Section, Section_Item 0, Section_Base: 0.16; Section, Section_Item 0, Section_H: 0.16; Section, Section_Item 0, Section_DistPrfX: 0; Section, Section_Item 0, Section_DistPrfY: 0; Section, Section_Item 0, Section_DispInPianta: 0; Section, Section_Item 0, Section_TipoForma: 0; Section, Section_Item 0, Section_AngleRot: 0; Section, Section_Item 0, Section_BrcX: 0; Section, Section_Item 0, Section_BrcY: 0
IFC_PSET_PolygonOffset - polygonOffsetFactor: 2; polygonOffsetUnits: 2
IFC_Pset_Alignment - Alignment_Sez: 0; Alignment_Poly: -1; Alignment_Nodo: -10; Alignment_TS: 0; Alignment_NODO_CLC: 0; Alignment_C_FC_SUP: 0
IFC_Pset_Caractéristiques - Numéro niveau: 02; Titre niveau: Rez-de-Jardin; Coupe: Ø160
IFC_Pset_Géométrie - Rotation: 0 deg
IFC_Pset_Système de Référence Altimétrique_SUPÉRIEUR - NIVEAU: HAUT Rez-de-Jardin; sous Niveau: <aucun>
IFC_Pset_Système de Référence Altimétrique_INFÉRIEUR - NIVEAU: Rez-de-Jardin
IFC_Pset_Données Métré - Surface en Plan: 200 cm2; Volume: 20000 cm3; Base Section: 16 cm; Hauteur Section: 16 cm; Diamètre Section: 16 cm
IFC_Pset_Matériaux - Principal: Chêne rouvre 02
Pset_ColumnCommon - Reference: Ø160 (..\Section circulaire\); Slope: 90 deg
BaseQuantities - CrossSectionArea: 200.807 cm2
Name | __RECOGNIZE__, ID = IFC_Pset_Caractéristiques, ID | 0, DocType | 0, Tag | 0, Crc | 1, DocType | 1, Tag | 1, Crc | Numérotation | Hauteur (cm) = NominalLength (cm) | Cote (cm) = IFC_Pset_Système de Référence Altimétrique_INFÉRIEUR, delta (cm) | IFC_Pset_Système de Référence Altimétrique_SUPÉRIEUR, delta (cm) | sous Niveau | Surface (latérale) (cm2) | OuterSurfaceArea (cm2) | TotalSurfaceArea (cm2) | GrossVolume (cm3) = NetVolume (cm3)
Poteau 1702909 | 1702909 | 2 | 0 | -1439514055 | 6 | -10 | 407626407 | 56 | 92.4004 | 110 | -139 | extérieur | 4600 | 4644.55 | 5046.16 | 18554.6
Poteau 1703071 | 1703071 | 6 | -10 | 407626407 | 2 | 0 | -1439514055 | 59 | 84.4004 | 110 | -147 | extérieur | 4200 | 4242.43 | 4644.04 | 16948.2
Poteau 1703077 | 1703077 | 6 | -10 | 407626407 | 2 | 0 | -1439514055 | 60 | 84.4004 | 110 | -147 | extérieur | 4200 | 4242.43 | 4644.04 | 16948.2
Poteau 1703012 | 1703012 | 2 | 0 | -1439514055 | 6 | -10 | 407626407 | 57 | 81.4004 | 110 | -150 | extérieur | 4100 | 4091.63 | 4493.24 | 16345.8
Poteau 1703015 | 1703015 | 2 | 0 | -1439514055 | 6 | -10 | 407626407 | 58 | 84.4004 | 110 | -147 | extérieur | 4200 | 4242.43 | 4644.04 | 16948.2
Poteau 1703097 | 1703097 | 6 | -10 | 407626407 | 2 | 0 | -1439514055 | 61 | 84.4004 | 110 | -147 | extérieur | 4200 | 4242.43 | 4644.04 | 16948.2
Poteau 1703135 | 1703135 | 6 | -10 | 407626407 | 2 | 0 | -1439514055 | 64 | 78.4004 | 110 | -153 | extérieur | 3900 | 3940.83 | 4342.45 | 15743.3
Poteau 1703102 | 1703102 | 6 | -10 | 407626407 | 2 | 0 | -1439514055 | 62 | 79.4004 | 110 | -152 | extérieur | 4000 | 3991.1 | 4392.71 | 15944.1
Poteau 1703132 | 1703132 | 6 | -10 | 407626407 | 2 | 0 | -1439514055 | 63 | 78.4004 | 110 | -153 | extérieur | 3900 | 3940.83 | 4342.45 | 15743.3
Poteau 69571 | 69571 | 6 | -10 | 407626407 | 2 | 0 | -1439514055 | 11 | 81.4004 | 110 | -150 | extérieur | 4100 | 4091.63 | 4493.24 | 16345.8
Poteau 69575 | 69575 | 6 | -10 | 407626407 | 2 | 0 | -1439514055 | 15 | 99.4004 | 60 | -132 | <aucun> | 5000 | 4996.41 | 5398.02 | 19960.3
Poteau 69585 | 69585 | 6 | -10 | 407626407 | 2 | 0 | -1439514055 | 24 | 96.4004 | 110 | -135 | extérieur | 4800 | 4845.61 | 5247.22 | 19357.9
Poteau 69586 | 69586 | 6 | -10 | 407626407 | 2 | 0 | -1439514055 | 25 | 98.4004 | 110 | -133 | extérieur | 4900 | 4946.14 | 5347.76 | 19759.5

# IfcColumn: Ø200 (7)
In: Couverture
Type - PredefinedType: USERDEFINED; Material: Brique (13)
Description: Poteau; Group: ...de matériaux et couleurs = Brique (13); ...de sections pour tiges = Ø200
__RECOGNIZE__ - TPLG: 200; TPLG_OD: 500; GENERATE: 1; Section_TypeForm: 0; AngleRotaz: 0; Section, Section_NumItems: 1; Section, Section_Item 0, Section_ID: 144; Section, Section_Item 0, Section_Desc: Ø200,00; Section, Section_Item 0, Section_Categ: 3; Section, Section_Item 0, Section_Tipo: 2; Section, Section_Item 0, Section_Base: 0.2; Section, Section_Item 0, Section_H: 0.2; Section, Section_Item 0, Section_DistPrfX: 0; Section, Section_Item 0, Section_DistPrfY: 0; Section, Section_Item 0, Section_DispInPianta: 0; Section, Section_Item 0, Section_TipoForma: 0; Section, Section_Item 0, Section_AngleRot: 0; Section, Section_Item 0, Section_BrcX: 0; Section, Section_Item 0, Section_BrcY: 0
CTLG_EXTERNAL_LINK - 0, DocType: 2; 0, Tag: 0; 0, Crc: -651744781; 1, DocType: 6; 1, Tag: -10; 1, Crc: -1926166186
IFC_PSET_PolygonOffset - polygonOffsetFactor: 2; polygonOffsetUnits: 2
IFC_Pset_Alignment - Alignment_Sez: 0; Alignment_Poly: -1; Alignment_Nodo: -10; Alignment_TS: 0; Alignment_NODO_CLC: 0; Alignment_C_FC_SUP: 0
IFC_Pset_Caractéristiques - Numéro niveau: 07; Titre niveau: Couverture; Coupe: Ø200
IFC_Pset_Géométrie - Rotation: 0 deg
IFC_Pset_Système de Référence Altimétrique_SUPÉRIEUR - sous Niveau: <aucun>
IFC_Pset_Système de Référence Altimétrique_INFÉRIEUR - NIVEAU: Couverture; sous Niveau: <aucun>
IFC_Pset_Données Métré - Surface en Plan: 300 cm2; Volume: 10000 cm3; Base Section: 20 cm; Hauteur Section: 20 cm; Diamètre Section: 20 cm
IFC_Pset_Matériaux - Principal: Brique (13)
Pset_ColumnCommon - Reference: Ø200 (..\Section circulaire\); Slope: 90 deg
BaseQuantities - CrossSectionArea: 313.761 cm2
Name | __RECOGNIZE__, ID = IFC_Pset_Caractéristiques, ID | Numérotation | Hauteur (cm) = NominalLength (cm) | Cote (cm) = IFC_Pset_Système de Référence Altimétrique_INFÉRIEUR, delta (cm) | IFC_Pset_Système de Référence Altimétrique_SUPÉRIEUR, delta (cm) | Surface (latérale) (cm2) | OuterSurfaceArea (cm2) | TotalSurfaceArea (cm2) | GrossVolume (cm3) = NetVolume (cm3)
Poteau 783073 | 783073 | 49 | 34 | 110 | 144 | 2100 | 2136.28 | 2763.8 | 10667.9
Poteau 783907 | 783907 | 50 | 34 | 110 | 144 | 2100 | 2136.28 | 2763.8 | 10667.9
Poteau 783067 | 783067 | 48 | 34 | 110 | 144 | 2100 | 2136.28 | 2763.8 | 10667.9
Poteau 783910 | 783910 | 51 | 34 | 110 | 144 | 2100 | 2136.28 | 2763.8 | 10667.9
Poteau 794476 | 794476 | 54 | 35 | 115 | 150 | 2200 | 2199.11 | 2826.64 | 10981.6
Poteau 783913 | 783913 | 52 | 34 | 110 | 144 | 2100 | 2136.28 | 2763.8 | 10667.9
Poteau 794473 | 794473 | 53 | 35 | 115 | 150 | 2200 | 2199.11 | 2826.64 | 10981.6

# IfcColumn: Ø200 (3)
In: Niveau 1
Type - PredefinedType: USERDEFINED; Material: Pierre du saint gottard
Description: Poteau; Group: ...de matériaux et couleurs = Pierre du saint gottard; ...de sections pour tiges = Ø200
__RECOGNIZE__ - TPLG: 200; TPLG_OD: 500; GENERATE: 1; Section_TypeForm: 0; AngleRotaz: 0; Section, Section_NumItems: 1; Section, Section_Item 0, Section_ID: 144; Section, Section_Item 0, Section_Desc: Ø200,00; Section, Section_Item 0, Section_Categ: 3; Section, Section_Item 0, Section_Tipo: 2; Section, Section_Item 0, Section_Base: 0.2; Section, Section_Item 0, Section_H: 0.2; Section, Section_Item 0, Section_DistPrfX: 0; Section, Section_Item 0, Section_DistPrfY: 0; Section, Section_Item 0, Section_DispInPianta: 0; Section, Section_Item 0, Section_TipoForma: 0; Section, Section_Item 0, Section_AngleRot: 0; Section, Section_Item 0, Section_BrcX: 0; Section, Section_Item 0, Section_BrcY: 0
CTLG_EXTERNAL_LINK - 0, DocType: 2; 0, Tag: 0; 0, Crc: 496042144; 1, DocType: 6; 1, Tag: -10; 1, Crc: -1926166186
IFC_PSET_PolygonOffset - polygonOffsetFactor: 2; polygonOffsetUnits: 2
IFC_Pset_Alignment - Alignment_Sez: 0; Alignment_Poly: -1; Alignment_Nodo: -10; Alignment_TS: 0; Alignment_NODO_CLC: 0; Alignment_C_FC_SUP: 0
IFC_Pset_Caractéristiques - Numéro niveau: 04; Titre niveau: Niveau 1; Coupe: Ø200
IFC_Pset_Géométrie - Hauteur: 201.115 cm; Rotation: 0 deg
IFC_Pset_Géométrie_POINT inférieur - Cote: 85 cm
IFC_Pset_Système de Référence Altimétrique_SUPÉRIEUR - NIVEAU: HAUT Niveau 1; delta: -90 cm; sous Niveau: <aucun>
IFC_Pset_Système de Référence Altimétrique_INFÉRIEUR - NIVEAU: Niveau 1; delta: 85 cm; sous Niveau: <aucun>
IFC_Pset_Données Métré - Surface (latérale): 12600 cm2; Surface en Plan: 300 cm2; Volume: 60000 cm3; Base Section: 20 cm; Hauteur Section: 20 cm; Diamètre Section: 20 cm
IFC_Pset_Matériaux - Principal: Pierre du saint gottard
Pset_ColumnCommon - Reference: Ø200 (..\Section circulaire\); Slope: 90 deg
BaseQuantities - NominalLength: 201.115 cm; CrossSectionArea: 313.761 cm2; OuterSurfaceArea: 12636.4 cm2; TotalSurfaceArea: 13264 cm2; GrossVolume: 63102 cm3; NetVolume: 63102 cm3
Name | __RECOGNIZE__, ID = IFC_Pset_Caractéristiques, ID | Numérotation
Poteau 440361 | 440361 | 47
Poteau 440337 | 440337 | 45
Poteau 440354 | 440354 | 46

# IfcCovering (71)
PredefinedType: CEILING; Material: Blanc
__RECOGNIZE__ - TPLG: 9020; TPLG_OD: 9020; GENERATE: 1
CTLG_EXTERNAL_LINK - 0, DocType: 2; 0, Tag: 0; 0, Crc: -746779066; 1, DocType: 2; 1, Tag: 101; 1, Crc: -746779066; 2, DocType: 2; 2, Tag: 102; 2, Crc: -746779066; 3, DocType: 2; 3, Tag: 103; 3, Crc: -746779066; 4, DocType: 2; 4, Tag: 104; 4, Crc: -746779066; 5, DocType: 2; 5, Tag: 105; 5, Crc: -746779066
IFC_PSET_PolygonOffset - polygonOffsetFactor: 2; polygonOffsetUnits: 2
IFC_Pset_Système de Référence Altimétrique_INFÉRIEUR - sous Niveau: <aucun>
IFC_Pset_Données Métré - Périmètre des parties accessibles: 0 cm; Surface parties accessibles: 0 cm2; Longueur structure support accessible: 0 cm; Numéro de panneaux accessibles: 0; Numéro de grillage accessibles: 0
Name | In | __RECOGNIZE__, ID = IFC_Pset_Caractéristiques, ID | 6, DocType | 6, Tag | 6, Crc | Numérotation | Numéro niveau | Titre niveau | NIVEAU | delta (cm) | Périmètre surfaces horizontales (cm) | Périmètre raccord verticaux (cm) | Périmètre (cm) | Surface horiziontale (cm2) | Surface raccords verticaux (cm2) | Surface (cm2) | GrossArea (cm2) | NetArea (cm2) | Group
Faux-plafond 72659 | Rez-de-Jardin | 72659 | 9 | 101 | -2060481618 | 16 | 02 | Rez-de-Jardin | HAUT Rez-de-Jardin (Rez-de-chaussée 1047) | -62.5 | 1442 | 0 | 1442 | 100000 | 0 | 100000 | 100002 | 100002 | ...de matériaux et couleurs = Blanc; ...de matériaux et couleurs - 1 = Blanc; ...de matériaux et couleurs - 2 = Blanc; ...de matériaux et couleurs - 3 = Blanc; ...de matériaux et couleurs - 4 = Blanc; ...de matériaux et couleurs - 5 = Blanc; ...de stratigraphies = Placoplâtre standard en plaques de 13
Faux-plafond 73183 | Rez-de-Jardin | 73183 | 9 | 101 | -2060481618 | 17 | 02 | Rez-de-Jardin | HAUT Rez-de-Jardin (Rez-de-chaussée 1047) | -64 | 2928 | 0 | 2928 | 513400 | 0 | 513400 | 513379 | 513379 | ...de matériaux et couleurs = Blanc; ...de matériaux et couleurs - 1 = Blanc; ...de matériaux et couleurs - 2 = Blanc; ...de matériaux et couleurs - 3 = Blanc; ...de matériaux et couleurs - 4 = Blanc; ...de matériaux et couleurs - 5 = Blanc; ...de stratigraphies = Placoplâtre standard en plaques de 13
Faux-plafond 73355 | Rez-de-Jardin | 73355 | 9 | 101 | -2060481618 | 18 | 02 | Rez-de-Jardin | HAUT Rez-de-Jardin (Rez-de-chaussée 1047) | -57.2 | 2938 | 0 | 2938 | 451500 | 0 | 451500 | 451499 | 451499 | ...de matériaux et couleurs = Blanc; ...de matériaux et couleurs - 1 = Blanc; ...de matériaux et couleurs - 2 = Blanc; ...de matériaux et couleurs - 3 = Blanc; ...de matériaux et couleurs - 4 = Blanc; ...de matériaux et couleurs - 5 = Blanc; ...de stratigraphies = Placoplâtre standard en plaques de 13
Faux-plafond 73404 | Rez-de-Jardin | 73404 | 9 | 101 | -2060481618 | 30 | 02 | Rez-de-Jardin | HAUT Rez-de-Jardin (Rez-de-chaussée 1047) | -36.2 | 1748 | 0 | 1748 | 166200 | 0 | 166200 | 166190 | 166190 | ...de matériaux et couleurs = Blanc; ...de matériaux et couleurs - 1 = Blanc; ...de matériaux et couleurs - 2 = Blanc; ...de matériaux et couleurs - 3 = Blanc; ...de matériaux et couleurs - 4 = Blanc; ...de matériaux et couleurs - 5 = Blanc; ...de stratigraphies = Placoplâtre standard en plaques de 13
Faux-plafond 73405 | Rez-de-Jardin | 73405 | 9 | 101 | -2060481618 | 31 | 02 | Rez-de-Jardin | HAUT Rez-de-Jardin (Rez-de-chaussée 1047) | -30.5 | 1693 | 0 | 1693 | 176700 | 0 | 176700 | 176704 | 176704 | ...de matériaux et couleurs = Blanc; ...de matériaux et couleurs - 1 = Blanc; ...de matériaux et couleurs - 2 = Blanc; ...de matériaux et couleurs - 3 = Blanc; ...de matériaux et couleurs - 4 = Blanc; ...de matériaux et couleurs - 5 = Blanc; ...de stratigraphies = Placoplâtre standard en plaques de 13
Faux-plafond 73402 | Rez-de-Jardin | 73402 | 9 | 101 | -2060481618 | 28 | 02 | Rez-de-Jardin | HAUT Rez-de-Jardin (Rez-de-chaussée 1047) | -38.6 | 556 | 0 | 556 | 18600 | 0 | 18600 | 18626.9 | 18626.9 | ...de matériaux et couleurs = Blanc; ...de matériaux et couleurs - 1 = Blanc; ...de matériaux et couleurs - 2 = Blanc; ...de matériaux et couleurs - 3 = Blanc; ...de matériaux et couleurs - 4 = Blanc; ...de matériaux et couleurs - 5 = Blanc; ...de stratigraphies = Placoplâtre standard en plaques de 13
Faux-plafond 73403 | Rez-de-Jardin | 73403 | 9 | 101 | -2060481618 | 29 | 02 | Rez-de-Jardin | HAUT Rez-de-Jardin (Rez-de-chaussée 1047) | -25.7 | 571 | 0 | 571 | 20200 | 0 | 20200 | 20162.2 | 20162.2 | ...de matériaux et couleurs = Blanc; ...de matériaux et couleurs - 1 = Blanc; ...de matériaux et couleurs - 2 = Blanc; ...de matériaux et couleurs - 3 = Blanc; ...de matériaux et couleurs - 4 = Blanc; ...de matériaux et couleurs - 5 = Blanc; ...de stratigraphies = Placoplâtre standard en plaques de 13
Faux-plafond 73406 | Rez-de-Jardin | 73406 | 9 | 101 | -2060481618 | 32 | 02 | Rez-de-Jardin | HAUT Rez-de-Jardin (Rez-de-chaussée 1047) | -24.4 | 1109 | 0 | 1109 | 69000 | 0 | 69000 | 68963 | 68963 | ...de matériaux et couleurs = Blanc; ...de matériaux et couleurs - 1 = Blanc; ...de matériaux et couleurs - 2 = Blanc; ...de matériaux et couleurs - 3 = Blanc; ...de matériaux et couleurs - 4 = Blanc; ...de matériaux et couleurs - 5 = Blanc; ...de stratigraphies = Placoplâtre standard en plaques de 13
Faux-plafond 73401 | Rez-de-Jardin | 73401 | 9 | 101 | -2060481618 | 27 | 02 | Rez-de-Jardin | HAUT Rez-de-Jardin (Rez-de-chaussée 1047) | -36.9 | 555 | 0 | 555 | 18500 | 0 | 18500 | 18546 | 18546 | ...de matériaux et couleurs = Blanc; ...de matériaux et couleurs - 1 = Blanc; ...de matériaux et couleurs - 2 = Blanc; ...de matériaux et couleurs - 3 = Blanc; ...de matériaux et couleurs - 4 = Blanc; ...de matériaux et couleurs - 5 = Blanc; ...de stratigraphies = Placoplâtre standard en plaques de 13
Faux-plafond 73358 | Rez-de-Jardin | 73358 | 9 | 101 | -2060481618 | 21 | 02 | Rez-de-Jardin | HAUT Rez-de-Jardin (Rez-de-chaussée 1047) | -50.2 | 1646 | 0 | 1646 | 194300 | 0 | 194300 | 194266 | 194266 | ...de matériaux et couleurs = Blanc; ...de matériaux et couleurs - 1 = Blanc; ...de matériaux et couleurs - 2 = Blanc; ...de matériaux et couleurs - 3 = Blanc; ...de matériaux et couleurs - 4 = Blanc; ...de matériaux et couleurs - 5 = Blanc; ...de stratigraphies = Placoplâtre standard en plaques de 13
Faux-plafond 73359 | Rez-de-Jardin | 73359 | 2 | 106 | -746779066 | 22 | 02 | Rez-de-Jardin | HAUT Rez-de-Jardin (Rez-de-chaussée 1047) | -38.4 | 1179 | 200 | 1379 | 37500 | 6200 | 43700 | 43655.6 | 43655.6 | ...de matériaux et couleurs = Blanc; ...de matériaux et couleurs - 1 = Blanc; ...de matériaux et couleurs - 2 = Blanc; ...de matériaux et couleurs - 6 = Blanc; ...de matériaux et couleurs - 7 = Blanc; ...de matériaux et couleurs - 3 = Blanc; ...de matériaux et couleurs - 4 = Blanc; ...de matériaux et couleurs - 5 = Blanc; ...de stratigraphies = Placoplâtre standard en plaques de 13; ...de matériaux et couleurs - 8 = Blanc; ...de matériaux et couleurs - 9 = Blanc; ...de matériaux et couleurs - 10 = Blanc; ...de matériaux et couleurs - 11 = Blanc; ...de stratigraphies - 1 = Placoplâtre standard en plaques de 13; ...de stratigraphies - 2 = Placoplâtre standard en plaques de 10 | CTLG_EXTERNAL_LINK - 7, DocType: 2; 7, Tag: 107; 7, Crc: -746779066; 8, DocType: 2; 8, Tag: 108; 8, Crc: -746779066; 9, DocType: 2; 9, Tag: 109; 9, Crc: -746779066; 10, DocType: 2; 10, Tag: 110; 10, Crc: -746779066; 11, DocType: 2; 11, Tag: 111; 11, Crc: -746779066; 12, DocType: 9; 12, Tag: 101; 12, Crc: -2060481618; 13, DocType: 9; 13, Tag: 102; 13, Crc: -2060481618; 14, DocType: 9; 14, Tag: 103; 14, Crc: 1896997855
Faux-plafond 73356 | Rez-de-Jardin | 73356 | 2 | 106 | -746779066 | 19 | 02 | Rez-de-Jardin | HAUT Rez-de-Jardin (Rez-de-chaussée 1047) | -33.5 | 1505 | 321 | 1826 | 69200 | 6800 | 76000 | 75990.9 | 75990.9 | ...de matériaux et couleurs = Blanc; ...de matériaux et couleurs - 1 = Blanc; ...de matériaux et couleurs - 2 = Blanc; ...de matériaux et couleurs - 6 = Blanc; ...de matériaux et couleurs - 7 = Blanc; ...de matériaux et couleurs - 3 = Blanc; ...de matériaux et couleurs - 4 = Blanc; ...de matériaux et couleurs - 5 = Blanc; ...de stratigraphies = Placoplâtre standard en plaques de 13; ...de matériaux et couleurs - 8 = Blanc; ...de matériaux et couleurs - 9 = Blanc; ...de matériaux et couleurs - 10 = Blanc; ...de matériaux et couleurs - 11 = Blanc; ...de matériaux et couleurs - 12 = Blanc; ...de stratigraphies - 1 = Placoplâtre standard en plaques de 13; ...de stratigraphies - 3 = Placoplâtre standard en plaques de 10; ...de stratigraphies - 2 = Placoplâtre standard en plaques de 10 | CTLG_EXTERNAL_LINK - 7, DocType: 2; 7, Tag: 107; 7, Crc: -746779066; 8, DocType: 2; 8, Tag: 108; 8, Crc: -746779066; 9, DocType: 2; 9, Tag: 109; 9, Crc: -746779066; 10, DocType: 2; 10, Tag: 110; 10, Crc: -746779066; 11, DocType: 2; 11, Tag: 111; 11, Crc: -746779066; 12, DocType: 2; 12, Tag: 112; 12, Crc: -746779066; 13, DocType: 9; 13, Tag: 101; 13, Crc: -2060481618; 14, DocType: 9; 14, Tag: 102; 14, Crc: -2060481618; 15, DocType: 9; 15, Tag: 103; 15, Crc: 1896997855; 16, DocType: 9; 16, Tag: 104; 16, Crc: 1896997855
Faux-plafond 73357 | Rez-de-Jardin | 73357 | 9 | 101 | -2060481618 | 20 | 02 | Rez-de-Jardin | HAUT Rez-de-Jardin (Rez-de-chaussée 1047) | -34.7 | 1310 | 0 | 1310 | 79300 | 0 | 79300 | 79264.2 | 79264.2 | ...de matériaux et couleurs = Blanc; ...de matériaux et couleurs - 1 = Blanc; ...de matériaux et couleurs - 2 = Blanc; ...de matériaux et couleurs - 3 = Blanc; ...de matériaux et couleurs - 4 = Blanc; ...de matériaux et couleurs - 5 = Blanc; ...de stratigraphies = Placoplâtre standard en plaques de 13
Faux-plafond 73399 | Rez-de-Jardin | 73399 | 2 | 106 | -746779066 | 25 | 02 | Rez-de-Jardin | HAUT Rez-de-Jardin (Rez-de-chaussée 1047) | -53 | 3632 | 350 | 3982 | 382000 | 7300 | 389300 | 389306 | 389306 | ...de matériaux et couleurs = Blanc; ...de matériaux et couleurs - 1 = Blanc; ...de matériaux et couleurs - 2 = Blanc; ...de matériaux et couleurs - 6 = Blanc; ...de matériaux et couleurs - 7 = Blanc; ...de matériaux et couleurs - 3 = Blanc; ...de matériaux et couleurs - 4 = Blanc; ...de matériaux et couleurs - 5 = Blanc; ...de stratigraphies = Placoplâtre standard en plaques de 13; ...de matériaux et couleurs - 8 = Blanc; ...de matériaux et couleurs - 9 = Blanc; ...de matériaux et couleurs - 10 = Blanc; ...de matériaux et couleurs - 11 = Blanc; ...de stratigraphies - 1 = Placoplâtre standard en plaques de 13; ...de stratigraphies - 2 = Placoplâtre standard en plaques de 10 | CTLG_EXTERNAL_LINK - 7, DocType: 2; 7, Tag: 107; 7, Crc: -746779066; 8, DocType: 2; 8, Tag: 108; 8, Crc: -746779066; 9, DocType: 2; 9, Tag: 109; 9, Crc: -746779066; 10, DocType: 2; 10, Tag: 110; 10, Crc: -746779066; 11, DocType: 2; 11, Tag: 111; 11, Crc: -746779066; 12, DocType: 9; 12, Tag: 101; 12, Crc: -2060481618; 13, DocType: 9; 13, Tag: 102; 13, Crc: -2060481618; 14, DocType: 9; 14, Tag: 103; 14, Crc: 1896997855
Faux-plafond 73400 | Rez-de-Jardin | 73400 | 9 | 101 | -2060481618 | 26 | 02 | Rez-de-Jardin | HAUT Rez-de-Jardin (Rez-de-chaussée 1047) | -39.3 | 692 | 0 | 692 | 29300 | 0 | 29300 | 29325.1 | 29325.1 | ...de matériaux et couleurs = Blanc; ...de matériaux et couleurs - 1 = Blanc; ...de matériaux et couleurs - 2 = Blanc; ...de matériaux et couleurs - 3 = Blanc; ...de matériaux et couleurs - 4 = Blanc; ...de matériaux et couleurs - 5 = Blanc; ...de stratigraphies = Placoplâtre standard en plaques de 13
Faux-plafond 73360 | Rez-de-Jardin | 73360 | 9 | 101 | -2060481618 | 23 | 02 | Rez-de-Jardin | HAUT Rez-de-Jardin (Rez-de-chaussée 1047) | -45.8 | 738 | 0 | 738 | 34000 | 0 | 34000 | 34036 | 34036 | ...de matériaux et couleurs = Blanc; ...de matériaux et couleurs - 1 = Blanc; ...de matériaux et couleurs - 2 = Blanc; ...de matériaux et couleurs - 3 = Blanc; ...de matériaux et couleurs - 4 = Blanc; ...de matériaux et couleurs - 5 = Blanc; ...de stratigraphies = Placoplâtre standard en plaques de 13
Faux-plafond 73361 | Rez-de-Jardin | 73361 | 9 | 101 | -2060481618 | 24 | 02 | Rez-de-Jardin | HAUT Rez-de-Jardin (Rez-de-chaussée 1047) | -45.9 | 1380 | 0 | 1380 | 102000 | 0 | 102000 | 101992 | 101992 | ...de matériaux et couleurs = Blanc; ...de matériaux et couleurs - 1 = Blanc; ...de matériaux et couleurs - 2 = Blanc; ...de matériaux et couleurs - 3 = Blanc; ...de matériaux et couleurs - 4 = Blanc; ...de matériaux et couleurs - 5 = Blanc; ...de stratigraphies = Placoplâtre standard en plaques de 13
Faux-plafond 6640 | Rez-de-chaussée | 6640 | 9 | 101 | -2060481618 | 12 | 03 | Rez-de-chaussée | HAUT Rez-de-chaussée (Niveau 1 2343) | -210 | 739 | 0 | 739 | 33900 | 0 | 33900 | 33881.9 | 33881.9 | ...de matériaux et couleurs = Blanc; ...de matériaux et couleurs - 1 = Blanc; ...de matériaux et couleurs - 2 = Blanc; ...de matériaux et couleurs - 3 = Blanc; ...de matériaux et couleurs - 4 = Blanc; ...de matériaux et couleurs - 5 = Blanc; ...de stratigraphies = Placoplâtre standard en plaques de 13
Faux-plafond 8413 | Rez-de-chaussée | 8413 | 9 | 101 | -2060481618 | 13 | 03 | Rez-de-chaussée | HAUT Rez-de-chaussée (Niveau 1 2343) | -80.703 | 1707 | 0 | 1707 | 219600 | 0 | 219600 | 219551 | 219551 | ...de matériaux et couleurs = Blanc; ...de matériaux et couleurs - 1 = Blanc; ...de matériaux et couleurs - 2 = Blanc; ...de matériaux et couleurs - 3 = Blanc; ...de matériaux et couleurs - 4 = Blanc; ...de matériaux et couleurs - 5 = Blanc; ...de stratigraphies = Placoplâtre standard en plaques de 13
Faux-plafond 6627 | Rez-de-chaussée | 6627 | 2 | 106 | -746779066 | 10 | 03 | Rez-de-chaussée | HAUT Rez-de-chaussée (Niveau 1 2343) | -124.906 | 1538 | 96 | 1634 | 96700 | 11700 | 108400 | 108447 | 108447 | ...de matériaux et couleurs = Blanc; ...de matériaux et couleurs - 1 = Blanc; ...de matériaux et couleurs - 2 = Blanc; ...de matériaux et couleurs - 6 = Blanc; ...de matériaux et couleurs - 7 = Blanc; ...de matériaux et couleurs - 3 = Blanc; ...de matériaux et couleurs - 4 = Blanc; ...de matériaux et couleurs - 5 = Blanc; ...de stratigraphies = Placoplâtre standard en plaques de 13; ...de matériaux et couleurs - 8 = Blanc; ...de matériaux et couleurs - 9 = Blanc; ...de matériaux et couleurs - 10 = Blanc; ...de matériaux et couleurs - 11 = Blanc; ...de stratigraphies - 1 = Placoplâtre standard en plaques de 13; ...de stratigraphies - 2 = Placoplâtre standard en plaques de 10 | CTLG_EXTERNAL_LINK - 7, DocType: 2; 7, Tag: 107; 7, Crc: -746779066; 8, DocType: 2; 8, Tag: 108; 8, Crc: -746779066; 9, DocType: 2; 9, Tag: 109; 9, Crc: -746779066; 10, DocType: 2; 10, Tag: 110; 10, Crc: -746779066; 11, DocType: 2; 11, Tag: 111; 11, Crc: -746779066; 12, DocType: 9; 12, Tag: 101; 12, Crc: -2060481618; 13, DocType: 9; 13, Tag: 102; 13, Crc: -2060481618; 14, DocType: 9; 14, Tag: 103; 14, Crc: 1896997855
Faux-plafond 6628 | Rez-de-chaussée | 6628 | 9 | 101 | -2060481618 | 11 | 03 | Rez-de-chaussée | HAUT Rez-de-chaussée (Niveau 1 2343) | -84.3947 | 2395 | 0 | 2395 | 345700 | 0 | 345700 | 345669 | 345669 | ...de matériaux et couleurs = Blanc; ...de matériaux et couleurs - 1 = Blanc; ...de matériaux et couleurs - 2 = Blanc; ...de matériaux et couleurs - 3 = Blanc; ...de matériaux et couleurs - 4 = Blanc; ...de matériaux et couleurs - 5 = Blanc; ...de stratigraphies = Placoplâtre standard en plaques de 13
Faux-plafond 11612 | Rez-de-chaussée | 11612 | 9 | 101 | -2060481618 | 14 | 03 | Rez-de-chaussée | HAUT Rez-de-chaussée (Niveau 1 2343) | -86.4015 | 1276 | 0 | 1276 | 50200 | 0 | 50200 | 50173.3 | 50173.3 | ...de matériaux et couleurs = Blanc; ...de matériaux et couleurs - 1 = Blanc; ...de matériaux et couleurs - 2 = Blanc; ...de matériaux et couleurs - 3 = Blanc; ...de matériaux et couleurs - 4 = Blanc; ...de matériaux et couleurs - 5 = Blanc; ...de stratigraphies = Placoplâtre standard en plaques de 13
Faux-plafond 13208 | Rez-de-chaussée | 13208 | 2 | 106 | -746779066 | 15 | 03 | Rez-de-chaussée | HAUT Rez-de-chaussée (Niveau 1 2343) | -211.655 | 6595 | 626 | 7221 | 268200 | 21100 | 289300 | 289337 | 289337 | ...de matériaux et couleurs = Blanc; ...de matériaux et couleurs - 1 = Blanc; ...de matériaux et couleurs - 2 = Blanc; ...de matériaux et couleurs - 6 = Blanc; ...de matériaux et couleurs - 7 = Blanc; ...de matériaux et couleurs - 3 = Blanc; ...de matériaux et couleurs - 4 = Blanc; ...de matériaux et couleurs - 5 = Blanc; ...de stratigraphies = Placoplâtre standard en plaques de 13; ...de matériaux et couleurs - 8 = Blanc; ...de matériaux et couleurs - 9 = Blanc; ...de matériaux et couleurs - 10 = Blanc; ...de matériaux et couleurs - 11 = Blanc; ...de matériaux et couleurs - 12 = Blanc; ...de matériaux et couleurs - 13 = Blanc; ...de matériaux et couleurs - 14 = Blanc; ...de matériaux et couleurs - 15 = Blanc; ...de matériaux et couleurs - 16 = Blanc; ...de stratigraphies - 1 = Placoplâtre standard en plaques de 13; ...de stratigraphies - 2 = Placoplâtre standard en plaques de 13; ...de matériaux et couleurs - 17 = Blanc; ...de matériaux et couleurs - 18 = Blanc; ...de matériaux et couleurs - 19 = Blanc; ...de matériaux et couleurs - 20 = Blanc; ...de matériaux et couleurs - 21 = Blanc; ...de matériaux et couleurs - 22 = Blanc; ...de matériaux et couleurs - 23 = Blanc; ...de stratigraphies - 3 = Placoplâtre standard en plaques de 13; ...de matériaux et couleurs - 24 = Blanc; ...de matériaux et couleurs - 25 = Blanc; ...de stratigraphies - 4 = Placoplâtre standard en plaques de 13; ...de matériaux et couleurs - 26 = Blanc; ...de matériaux et couleurs - 27 = Blanc; ...de matériaux et couleurs - 28 = Blanc; ...de matériaux et couleurs - 29 = Blanc; ...de matériaux et couleurs - 30 = Blanc; ...de matériaux et couleurs - 31 = Blanc; ...de matériaux et couleurs - 32 = Blanc; ...de matériaux et couleurs - 33 = Blanc; ...de matériaux et couleurs - 34 = Blanc; ...de matériaux et couleurs - 35 = Blanc; ...de matériaux et couleurs - 36 = Blanc; ...de matériaux et couleurs - 37 = Blanc; ...de matériaux et couleurs - 38 = Blanc; ...de matériaux et couleurs - 39 = Blanc; ...de matériaux et couleurs - 40 = Blanc; ...de matériaux et couleurs - 41 = Blanc; ...de matériaux et couleurs - 42 = Blanc; ...de matériaux et couleurs - 43 = Blanc; ...de matériaux et couleurs - 44 = Blanc; ...de matériaux et couleurs - 45 = Blanc; ...de matériaux et couleurs - 46 = Blanc; ...de matériaux et couleurs - 47 = Blanc; ...de matériaux et couleurs - 48 = Blanc; ...de matériaux et couleurs - 49 = Blanc; ...de matériaux et couleurs - 50 = Blanc; ...de matériaux et couleurs - 51 = Blanc; ...de matériaux et couleurs - 52 = Blanc; ...de matériaux et couleurs - 53 = Blanc; ...de matériaux et couleurs - 54 = Blanc; ...de matériaux et couleurs - 55 = Blanc; ...de stratigraphies - 5 = Placoplâtre standard en plaques de 13; ...de stratigraphies - 6 = Placoplâtre standard en plaques de 13; ...de stratigraphies - 7 = Placoplâtre standard en plaques de 13; ...de stratigraphies - 8 = Placoplâtre standard en plaques de 13; ...de stratigraphies - 9 = Placoplâtre standard en plaques de 13; ...de stratigraphies - 10 = Placoplâtre standard en plaques de 10; ...de stratigraphies - 11 = Placoplâtre standard en plaques de 10; ...de stratigraphies - 12 = Placoplâtre standard en plaques de 10; ...de stratigraphies - 13 = Placoplâtre standard en plaques de 10; ...de stratigraphies - 14 = Placoplâtre standard en plaques de 10 | CTLG_EXTERNAL_LINK - 7, DocType: 2; 7, Tag: 107; 7, Crc: -746779066; 8, DocType: 2; 8, Tag: 108; 8, Crc: -746779066; 9, DocType: 2; 9, Tag: 109; 9, Crc: -746779066; 10, DocType: 2; 10, Tag: 110; 10, Crc: -746779066; 11, DocType: 2; 11, Tag: 111; 11, Crc: -746779066; 12, DocType: 2; 12, Tag: 112; 12, Crc: -746779066; 13, DocType: 2; 13, Tag: 113; 13, Crc: -746779066; 14, DocType: 2; 14, Tag: 114; 14, Crc: -746779066; 15, DocType: 2; 15, Tag: 115; 15, Crc: -746779066; 16, DocType: 2; 16, Tag: 116; 16, Crc: -746779066; 17, DocType: 2; 17, Tag: 117; 17, Crc: -746779066; 18, DocType: 2; 18, Tag: 118; 18, Crc: -746779066; 19, DocType: 2; 19, Tag: 119; 19, Crc: -746779066; 20, DocType: 2; 20, Tag: 120; 20, Crc: -746779066; 21, DocType: 2; 21, Tag: 121; 21, Crc: -746779066; 22, DocType: 2; 22, Tag: 122; 22, Crc: -746779066; 23, DocType: 2; 23, Tag: 123; 23, Crc: -746779066; 24, DocType: 2; 24, Tag: 124; 24, Crc: -746779066; 25, DocType: 2; 25, Tag: 125; 25, Crc: -746779066; 26, DocType: 2; 26, Tag: 126; 26, Crc: -746779066; 27, DocType: 2; 27, Tag: 127; 27, Crc: -746779066; 28, DocType: 2; 28, Tag: 128; 28, Crc: -746779066; 29, DocType: 2; 29, Tag: 129; 29, Crc: -746779066; 30, DocType: 2; 30, Tag: 130; 30, Crc: -746779066; 31, DocType: 2; 31, Tag: 131; 31, Crc: -746779066; 32, DocType: 2; 32, Tag: 132; 32, Crc: -746779066; 33, DocType: 2; 33, Tag: 133; 33, Crc: -746779066; 34, DocType: 2; 34, Tag: 134; 34, Crc: -746779066; 35, DocType: 2; 35, Tag: 135; 35, Crc: -746779066; 36, DocType: 2; 36, Tag: 136; 36, Crc: -746779066; 37, DocType: 2; 37, Tag: 137; 37, Crc: -746779066; 38, DocType: 2; 38, Tag: 138; 38, Crc: -746779066; 39, DocType: 2; 39, Tag: 139; 39, Crc: -746779066; 40, DocType: 2; 40, Tag: 140; 40, Crc: -746779066; 41, DocType: 2; 41, Tag: 141; 41, Crc: -746779066; 42, DocType: 2; 42, Tag: 142; 42, Crc: -746779066; 43, DocType: 2; 43, Tag: 143; 43, Crc: -746779066; 44, DocType: 2; 44, Tag: 144; 44, Crc: -746779066; 45, DocType: 2; 45, Tag: 145; 45, Crc: -746779066; 46, DocType: 2; 46, Tag: 146; 46, Crc: -746779066; 47, DocType: 2; 47, Tag: 147; 47, Crc: -746779066; 48, DocType: 2; 48, Tag: 148; 48, Crc: -746779066; 49, DocType: 2; 49, Tag: 149; 49, Crc: -746779066; 50, DocType: 2; 50, Tag: 150; 50, Crc: -746779066; 51, DocType: 2; 51, Tag: 151; 51, Crc: -746779066; 52, DocType: 2; 52, Tag: 152; 52, Crc: -746779066; 53, DocType: 2; 53, Tag: 153; 53, Crc: -746779066; 54, DocType: 2; 54, Tag: 154; 54, Crc: -746779066; 55, DocType: 2; 55, Tag: 155; 55, Crc: -746779066; 56, DocType: 9; 56, Tag: 101; 56, Crc: -2060481618; 57, DocType: 9; 57, Tag: 102; 57, Crc: -2060481618; 58, DocType: 9; 58, Tag: 103; 58, Crc: -2060481618; 59, DocType: 9; 59, Tag: 104; 59, Crc: -2060481618; 60, DocType: 9; 60, Tag: 105; 60, Crc: -2060481618; 61, DocType: 9; 61, Tag: 106; 61, Crc: -2060481618; 62, DocType: 9; 62, Tag: 107; 62, Crc: -2060481618; 63, DocType: 9; 63, Tag: 108; 63, Crc: -2060481618; 64, DocType: 9; 64, Tag: 109; 64, Crc: -2060481618; 65, DocType: 9; 65, Tag: 110; 65, Crc: -2060481618; 66, DocType: 9; 66, Tag: 111; 66, Crc: 1896997855; 67, DocType: 9; 67, Tag: 112; 67, Crc: 1896997855; 68, DocType: 9; 68, Tag: 113; 68, Crc: 1896997855; 69, DocType: 9; 69, Tag: 114; 69, Crc: 1896997855; 70, DocType: 9; 70, Tag: 115; 70, Crc: 1896997855
Faux-plafond 6295 | Rez-de-chaussée | 6295 | 9 | 101 | -2060481618 | 09 | 03 | Rez-de-chaussée | HAUT Rez-de-chaussée (Niveau 1 2343) | -95.3017 | 3095 | 0 | 3095 | 575500 | 0 | 575500 | 575536 | 575536 | ...de matériaux et couleurs = Blanc; ...de matériaux et couleurs - 1 = Blanc; ...de matériaux et couleurs - 2 = Blanc; ...de matériaux et couleurs - 3 = Blanc; ...de matériaux et couleurs - 4 = Blanc; ...de matériaux et couleurs - 5 = Blanc; ...de stratigraphies = Placoplâtre standard en plaques de 13
Faux-plafond 6012 | Rez-de-chaussée | 6012 | 9 | 101 | -2060481618 | 03 | 03 | Rez-de-chaussée | HAUT Rez-de-chaussée (Niveau 1 2343) | -232.5 | 1083 | 0 | 1083 | 52900 | 0 | 52900 | 52900.3 | 52900.3 | ...de matériaux et couleurs = Blanc; ...de matériaux et couleurs - 1 = Blanc; ...de matériaux et couleurs - 2 = Blanc; ...de matériaux et couleurs - 3 = Blanc; ...de matériaux et couleurs - 4 = Blanc; ...de matériaux et couleurs - 5 = Blanc; ...de stratigraphies = Placoplâtre standard en plaques de 13
Faux-plafond 6070 | Rez-de-chaussée | 6070 | 9 | 101 | -2060481618 | 04 | 03 | Rez-de-chaussée | HAUT Rez-de-chaussée (Niveau 1 2343) | -206.305 | 536 | 0 | 536 | 17900 | 0 | 17900 | 17880.5 | 17880.5 | ...de matériaux et couleurs = Blanc; ...de matériaux et couleurs - 1 = Blanc; ...de matériaux et couleurs - 2 = Blanc; ...de matériaux et couleurs - 3 = Blanc; ...de matériaux et couleurs - 4 = Blanc; ...de matériaux et couleurs - 5 = Blanc; ...de stratigraphies = Placoplâtre standard en plaques de 13
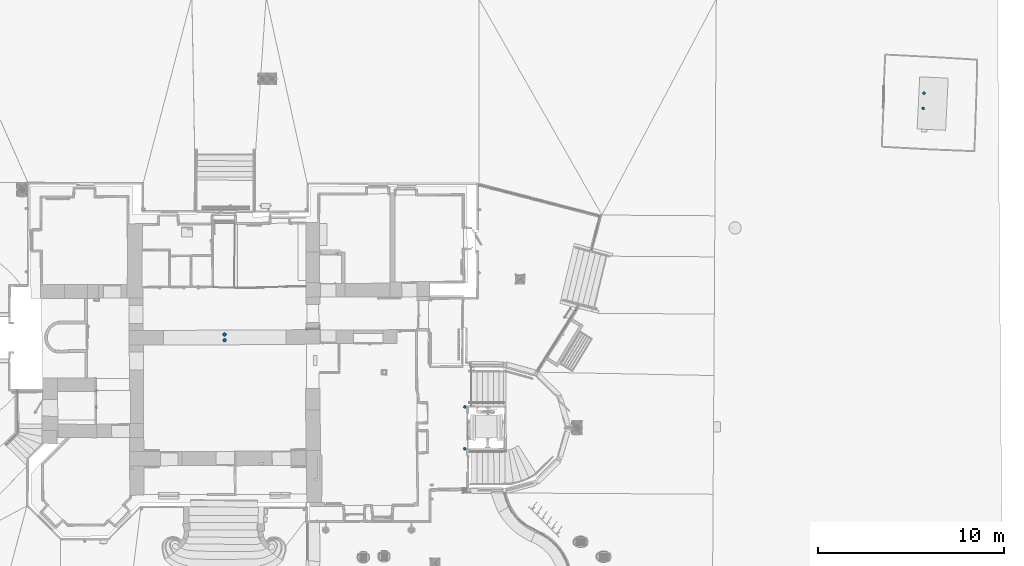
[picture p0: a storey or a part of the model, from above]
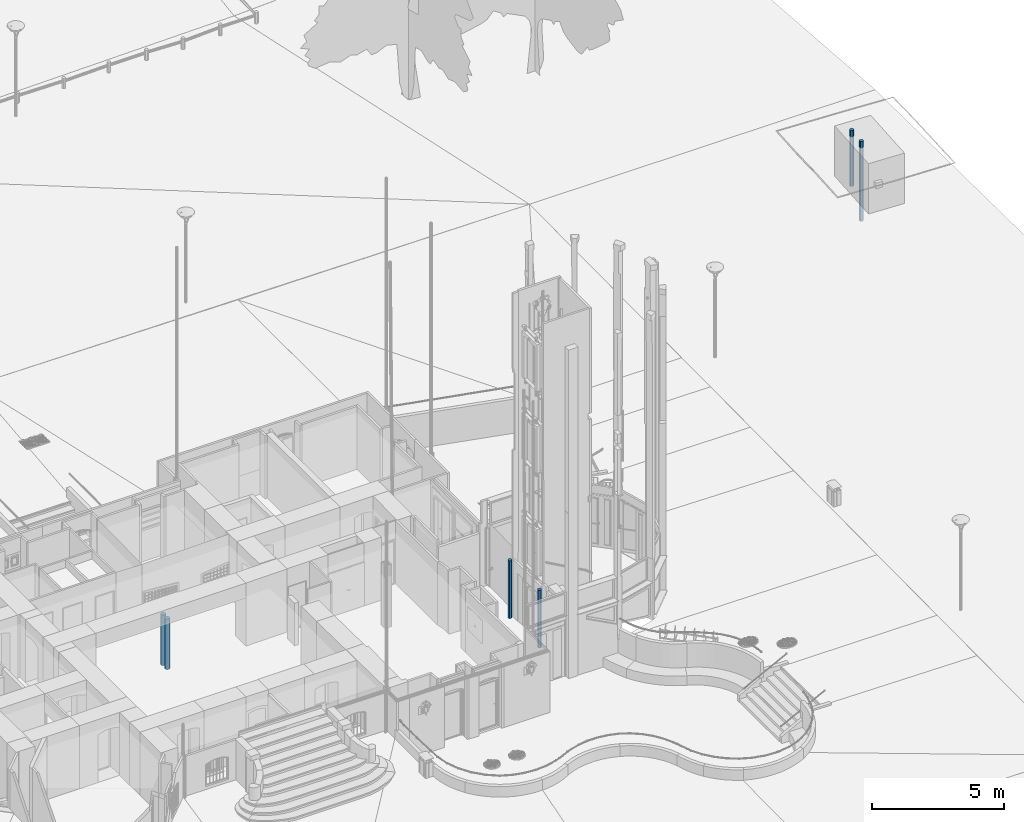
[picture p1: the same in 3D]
Properties of the parts of a building model (IFC2X3), part 5 of 37

# IfcCovering (71)
Name | In | __RECOGNIZE__, ID = IFC_Pset_Caractéristiques, ID | 6, DocType | 6, Tag | 6, Crc | Numérotation | Numéro niveau | Titre niveau | NIVEAU | delta (cm) | Périmètre surfaces horizontales (cm) | Périmètre raccord verticaux (cm) | Périmètre (cm) | Surface horiziontale (cm2) | Surface raccords verticaux (cm2) | Surface (cm2) | GrossArea (cm2) | NetArea (cm2) | Group
Faux-plafond 3684 | Rez-de-chaussée | 3684 | 9 | 101 | -2060481618 | 01 | 03 | Rez-de-chaussée | HAUT Rez-de-chaussée (Niveau 1 2343) | -230.209 | 755 | 0 | 755 | 33900 | 0 | 33900 | 33883.8 | 33883.8 | ...de matériaux et couleurs = Blanc; ...de matériaux et couleurs - 1 = Blanc; ...de matériaux et couleurs - 2 = Blanc; ...de matériaux et couleurs - 3 = Blanc; ...de matériaux et couleurs - 4 = Blanc; ...de matériaux et couleurs - 5 = Blanc; ...de stratigraphies = Placoplâtre standard en plaques de 13
Faux-plafond 3685 | Rez-de-chaussée | 3685 | 9 | 101 | -2060481618 | 02 | 03 | Rez-de-chaussée | HAUT Rez-de-chaussée (Niveau 1 2343) | -231.89 | 715 | 0 | 715 | 31500 | 0 | 31500 | 31475.5 | 31475.5 | ...de matériaux et couleurs = Blanc; ...de matériaux et couleurs - 1 = Blanc; ...de matériaux et couleurs - 2 = Blanc; ...de matériaux et couleurs - 3 = Blanc; ...de matériaux et couleurs - 4 = Blanc; ...de matériaux et couleurs - 5 = Blanc; ...de stratigraphies = Placoplâtre standard en plaques de 13
Faux-plafond 6188 | Rez-de-chaussée | 6188 | 9 | 101 | -2060481618 | 07 | 03 | Rez-de-chaussée | HAUT Rez-de-chaussée (Niveau 1 2343) | -97.0967 | 3087 | 0 | 3087 | 571700 | 0 | 571700 | 571703 | 571703 | ...de matériaux et couleurs = Blanc; ...de matériaux et couleurs - 1 = Blanc; ...de matériaux et couleurs - 2 = Blanc; ...de matériaux et couleurs - 3 = Blanc; ...de matériaux et couleurs - 4 = Blanc; ...de matériaux et couleurs - 5 = Blanc; ...de stratigraphies = Placoplâtre standard en plaques de 13
Faux-plafond 6189 | Rez-de-chaussée | 6189 | 9 | 101 | -2060481618 | 08 | 03 | Rez-de-chaussée | HAUT Rez-de-chaussée (Niveau 1 2343) | -80.0982 | 2054 | 0 | 2054 | 263700 | 0 | 263700 | 263701 | 263701 | ...de matériaux et couleurs = Blanc; ...de matériaux et couleurs - 1 = Blanc; ...de matériaux et couleurs - 2 = Blanc; ...de matériaux et couleurs - 3 = Blanc; ...de matériaux et couleurs - 4 = Blanc; ...de matériaux et couleurs - 5 = Blanc; ...de stratigraphies = Placoplâtre standard en plaques de 13
Faux-plafond 6071 | Rez-de-chaussée | 6071 | 9 | 101 | -2060481618 | 05 | 03 | Rez-de-chaussée | HAUT Rez-de-chaussée (Niveau 1 2343) | -199.795 | 1588 | 0 | 1588 | 128200 | 0 | 128200 | 128190 | 128190 | ...de matériaux et couleurs = Blanc; ...de matériaux et couleurs - 1 = Blanc; ...de matériaux et couleurs - 2 = Blanc; ...de matériaux et couleurs - 3 = Blanc; ...de matériaux et couleurs - 4 = Blanc; ...de matériaux et couleurs - 5 = Blanc; ...de stratigraphies = Placoplâtre standard en plaques de 13
Faux-plafond 6095 | Rez-de-chaussée | 6095 | 9 | 101 | -2060481618 | 06 | 03 | Rez-de-chaussée | HAUT Rez-de-chaussée (Niveau 1 2343) | -81.8008 | 2659 | 0 | 2659 | 418200 | 0 | 418200 | 418187 | 418187 | ...de matériaux et couleurs = Blanc; ...de matériaux et couleurs - 1 = Blanc; ...de matériaux et couleurs - 2 = Blanc; ...de matériaux et couleurs - 3 = Blanc; ...de matériaux et couleurs - 4 = Blanc; ...de matériaux et couleurs - 5 = Blanc; ...de stratigraphies = Placoplâtre standard en plaques de 13
Faux-plafond 132697 | Niveau 1 | 132697 | 9 | 101 | -2060481618 | 48 | 04 | Niveau 1 | HAUT Niveau 1 (Niveau 2 13545) | -76.0166 | 1630 | 0 | 1630 | 200200 | 0 | 200200 | 200236 | 200236 | ...de matériaux et couleurs = Blanc; ...de matériaux et couleurs - 1 = Blanc; ...de matériaux et couleurs - 2 = Blanc; ...de matériaux et couleurs - 3 = Blanc; ...de matériaux et couleurs - 4 = Blanc; ...de matériaux et couleurs - 5 = Blanc; ...de stratigraphies = Placoplâtre standard en plaques de 13
Faux-plafond 132688 | Niveau 1 | 132688 | 9 | 101 | -2060481618 | 46 | 04 | Niveau 1 | HAUT Niveau 1 (Niveau 2 13545) | -75.6089 | 1391 | 0 | 1391 | 93600 | 0 | 93600 | 93645.9 | 93645.9 | ...de matériaux et couleurs = Blanc; ...de matériaux et couleurs - 1 = Blanc; ...de matériaux et couleurs - 2 = Blanc; ...de matériaux et couleurs - 3 = Blanc; ...de matériaux et couleurs - 4 = Blanc; ...de matériaux et couleurs - 5 = Blanc; ...de stratigraphies = Placoplâtre standard en plaques de 13
Faux-plafond 132692 | Niveau 1 | 132692 | 2 | 106 | -746779066 | 47 | 04 | Niveau 1 | HAUT Niveau 1 (Niveau 2 13545) | -52.5 | 1977 | 454 | 2432 | 88500 | 11700 | 100200 | 100219 | 100219 | ...de matériaux et couleurs = Blanc; ...de matériaux et couleurs - 1 = Blanc; ...de matériaux et couleurs - 2 = Blanc; ...de matériaux et couleurs - 6 = Blanc; ...de matériaux et couleurs - 7 = Blanc; ...de matériaux et couleurs - 3 = Blanc; ...de matériaux et couleurs - 4 = Blanc; ...de matériaux et couleurs - 5 = Blanc; ...de stratigraphies = Placoplâtre standard en plaques de 13; ...de matériaux et couleurs - 8 = Blanc; ...de matériaux et couleurs - 9 = Blanc; ...de matériaux et couleurs - 10 = Blanc; ...de matériaux et couleurs - 11 = Blanc; ...de matériaux et couleurs - 12 = Blanc; ...de matériaux et couleurs - 13 = Blanc; ...de matériaux et couleurs - 14 = Blanc; ...de matériaux et couleurs - 15 = Blanc; ...de matériaux et couleurs - 16 = Blanc; ...de stratigraphies - 1 = Placoplâtre standard en plaques de 13; ...de stratigraphies - 2 = Placoplâtre standard en plaques de 13; ...de stratigraphies - 3 = Placoplâtre standard en plaques de 10 | CTLG_EXTERNAL_LINK - 7, DocType: 2; 7, Tag: 107; 7, Crc: -746779066; 8, DocType: 2; 8, Tag: 108; 8, Crc: -746779066; 9, DocType: 2; 9, Tag: 109; 9, Crc: -746779066; 10, DocType: 2; 10, Tag: 110; 10, Crc: -746779066; 11, DocType: 2; 11, Tag: 111; 11, Crc: -746779066; 12, DocType: 2; 12, Tag: 112; 12, Crc: -746779066; 13, DocType: 2; 13, Tag: 113; 13, Crc: -746779066; 14, DocType: 2; 14, Tag: 114; 14, Crc: -746779066; 15, DocType: 2; 15, Tag: 115; 15, Crc: -746779066; 16, DocType: 2; 16, Tag: 116; 16, Crc: -746779066; 17, DocType: 9; 17, Tag: 101; 17, Crc: -2060481618; 18, DocType: 9; 18, Tag: 102; 18, Crc: -2060481618; 19, DocType: 9; 19, Tag: 103; 19, Crc: -2060481618; 20, DocType: 9; 20, Tag: 104; 20, Crc: 1896997855
Faux-plafond 128665 | Niveau 1 | 128665 | 9 | 101 | -2060481618 | 45 | 04 | Niveau 1 | HAUT Niveau 1 (Niveau 2 13545) | -79.5 | 2470 | 0 | 2470 | 347600 | 0 | 347600 | 347613 | 347613 | ...de matériaux et couleurs = Blanc; ...de matériaux et couleurs - 1 = Blanc; ...de matériaux et couleurs - 2 = Blanc; ...de matériaux et couleurs - 3 = Blanc; ...de matériaux et couleurs - 4 = Blanc; ...de matériaux et couleurs - 5 = Blanc; ...de stratigraphies = Placoplâtre standard en plaques de 13
Faux-plafond 111276 | Niveau 1 | 111276 | 9 | 101 | -2060481618 | 39 | 04 | Niveau 1 | HAUT Niveau 1 (Niveau 2 13545) | -105 | 3007 | 0 | 3007 | 541200 | 0 | 541200 | 541249 | 541249 | ...de matériaux et couleurs = Blanc; ...de matériaux et couleurs - 1 = Blanc; ...de matériaux et couleurs - 2 = Blanc; ...de matériaux et couleurs - 3 = Blanc; ...de matériaux et couleurs - 4 = Blanc; ...de matériaux et couleurs - 5 = Blanc; ...de stratigraphies = Placoplâtre standard en plaques de 13
Faux-plafond 115764 | Niveau 1 | 115764 | 9 | 101 | -2060481618 | 40 | 04 | Niveau 1 | HAUT Niveau 1 (Niveau 2 13545) | -74 | 1977 | 0 | 1977 | 244300 | 0 | 244300 | 244344 | 244344 | ...de matériaux et couleurs = Blanc; ...de matériaux et couleurs - 1 = Blanc; ...de matériaux et couleurs - 2 = Blanc; ...de matériaux et couleurs - 3 = Blanc; ...de matériaux et couleurs - 4 = Blanc; ...de matériaux et couleurs - 5 = Blanc; ...de stratigraphies = Placoplâtre standard en plaques de 13
Faux-plafond 103157 | Niveau 1 | 103157 | 9 | 101 | -2060481618 | 37 | 04 | Niveau 1 | HAUT Niveau 1 (Niveau 2 13545) | -76.3089 | 2578 | 0 | 2578 | 394000 | 0 | 394000 | 393999 | 393999 | ...de matériaux et couleurs = Blanc; ...de matériaux et couleurs - 1 = Blanc; ...de matériaux et couleurs - 2 = Blanc; ...de matériaux et couleurs - 3 = Blanc; ...de matériaux et couleurs - 4 = Blanc; ...de matériaux et couleurs - 5 = Blanc; ...de stratigraphies = Placoplâtre standard en plaques de 13
Faux-plafond 104278 | Niveau 1 | 104278 | 9 | 101 | -2060481618 | 38 | 04 | Niveau 1 | HAUT Niveau 1 (Niveau 2 13545) | -77.4089 | 2272 | 0 | 2272 | 209900 | 0 | 209900 | 209892 | 209892 | ...de matériaux et couleurs = Blanc; ...de matériaux et couleurs - 1 = Blanc; ...de matériaux et couleurs - 2 = Blanc; ...de matériaux et couleurs - 3 = Blanc; ...de matériaux et couleurs - 4 = Blanc; ...de matériaux et couleurs - 5 = Blanc; ...de stratigraphies = Placoplâtre standard en plaques de 13
Faux-plafond 121127 | Niveau 1 | 121127 | 9 | 101 | -2060481618 | 43 | 04 | Niveau 1 | HAUT Niveau 1 (Niveau 2 13545) | -157 | 463 | 0 | 463 | 11700 | 0 | 11700 | 11737.9 | 11737.9 | ...de matériaux et couleurs = Blanc; ...de matériaux et couleurs - 1 = Blanc; ...de matériaux et couleurs - 2 = Blanc; ...de matériaux et couleurs - 3 = Blanc; ...de matériaux et couleurs - 4 = Blanc; ...de matériaux et couleurs - 5 = Blanc; ...de stratigraphies = Placoplâtre standard en plaques de 13
Faux-plafond 121128 | Niveau 1 | 121128 | 9 | 101 | -2060481618 | 44 | 04 | Niveau 1 | HAUT Niveau 1 (Niveau 2 13545) | -157 | 617 | 0 | 617 | 17800 | 0 | 17800 | 17769 | 17769 | ...de matériaux et couleurs = Blanc; ...de matériaux et couleurs - 1 = Blanc; ...de matériaux et couleurs - 2 = Blanc; ...de matériaux et couleurs - 3 = Blanc; ...de matériaux et couleurs - 4 = Blanc; ...de matériaux et couleurs - 5 = Blanc; ...de stratigraphies = Placoplâtre standard en plaques de 13
Faux-plafond 116302 | Niveau 1 | 116302 | 9 | 101 | -2060481618 | 41 | 04 | Niveau 1 | HAUT Niveau 1 (Niveau 2 13545) | -125 | 1025 | 0 | 1025 | 47800 | 0 | 47800 | 47793.7 | 47793.7 | ...de matériaux et couleurs = Blanc; ...de matériaux et couleurs - 1 = Blanc; ...de matériaux et couleurs - 2 = Blanc; ...de matériaux et couleurs - 3 = Blanc; ...de matériaux et couleurs - 4 = Blanc; ...de matériaux et couleurs - 5 = Blanc; ...de stratigraphies = Placoplâtre standard en plaques de 13
Faux-plafond 120672 | Niveau 1 | 120672 | 9 | 101 | -2060481618 | 42 | 04 | Niveau 1 | HAUT Niveau 1 (Niveau 2 13545) | -116.809 | 741 | 0 | 741 | 33600 | 0 | 33600 | 33602.3 | 33602.3 | ...de matériaux et couleurs = Blanc; ...de matériaux et couleurs - 1 = Blanc; ...de matériaux et couleurs - 2 = Blanc; ...de matériaux et couleurs - 3 = Blanc; ...de matériaux et couleurs - 4 = Blanc; ...de matériaux et couleurs - 5 = Blanc; ...de stratigraphies = Placoplâtre standard en plaques de 13
Faux-plafond 449649 | Niveau 1 | 449649 | 9 | 101 | -2060481618 | 61 | 04 | Niveau 1 | HAUT Niveau 1 (Niveau 2 13545) | -17.712 | 2180 | 0 | 2180 | 170500 | 0 | 170500 | 170498 | 170498 | ...de matériaux et couleurs = Blanc; ...de matériaux et couleurs - 1 = Blanc; ...de matériaux et couleurs - 2 = Blanc; ...de matériaux et couleurs - 3 = Blanc; ...de matériaux et couleurs - 4 = Blanc; ...de matériaux et couleurs - 5 = Blanc; ...de stratigraphies = Placoplâtre standard en plaques de 13
Faux-plafond 103156 | Niveau 1 | 103156 | 9 | 101 | -2060481618 | 36 | 04 | Niveau 1 | HAUT Niveau 1 (Niveau 2 13545) | -76 | 1505 | 0 | 1505 | 112300 | 0 | 112300 | 112254 | 112254 | ...de matériaux et couleurs = Blanc; ...de matériaux et couleurs - 1 = Blanc; ...de matériaux et couleurs - 2 = Blanc; ...de matériaux et couleurs - 3 = Blanc; ...de matériaux et couleurs - 4 = Blanc; ...de matériaux et couleurs - 5 = Blanc; ...de stratigraphies = Placoplâtre standard en plaques de 13
Faux-plafond 99982 | Niveau 1 | 99982 | 9 | 101 | -2060481618 | 34 | 04 | Niveau 1 | HAUT Niveau 1 (Niveau 2 13545) | -138 | 538 | 0 | 538 | 17700 | 0 | 17700 | 17690.6 | 17690.6 | ...de matériaux et couleurs = Blanc; ...de matériaux et couleurs - 1 = Blanc; ...de matériaux et couleurs - 2 = Blanc; ...de matériaux et couleurs - 3 = Blanc; ...de matériaux et couleurs - 4 = Blanc; ...de matériaux et couleurs - 5 = Blanc; ...de stratigraphies = Placoplâtre standard en plaques de 13
Faux-plafond 103096 | Niveau 1 | 103096 | 9 | 101 | -2060481618 | 35 | 04 | Niveau 1 | HAUT Niveau 1 (Niveau 2 13545) | -138.3 | 731 | 0 | 731 | 32800 | 0 | 32800 | 32787 | 32787 | ...de matériaux et couleurs = Blanc; ...de matériaux et couleurs - 1 = Blanc; ...de matériaux et couleurs - 2 = Blanc; ...de matériaux et couleurs - 3 = Blanc; ...de matériaux et couleurs - 4 = Blanc; ...de matériaux et couleurs - 5 = Blanc; ...de stratigraphies = Placoplâtre standard en plaques de 13
Faux-plafond 99981 | Niveau 1 | 99981 | 9 | 101 | -2060481618 | 33 | 04 | Niveau 1 | HAUT Niveau 1 (Niveau 2 13545) | -155.5 | 546 | 0 | 546 | 18300 | 0 | 18300 | 18318.1 | 18318.1 | ...de matériaux et couleurs = Blanc; ...de matériaux et couleurs - 1 = Blanc; ...de matériaux et couleurs - 2 = Blanc; ...de matériaux et couleurs - 3 = Blanc; ...de matériaux et couleurs - 4 = Blanc; ...de matériaux et couleurs - 5 = Blanc; ...de stratigraphies = Placoplâtre standard en plaques de 13
Faux-plafond 152115 | Niveau 2 | 152115 | 9 | 101 | -2060481618 | 49 | 05 | Niveau 2 | HAUT Niveau 2 (Mezzanine 49003) | -26.5 | 533 | 0 | 533 | 17300 | 0 | 17300 | 17324.8 | 17324.8 | ...de matériaux et couleurs = Blanc; ...de matériaux et couleurs - 1 = Blanc; ...de matériaux et couleurs - 2 = Blanc; ...de matériaux et couleurs - 3 = Blanc; ...de matériaux et couleurs - 4 = Blanc; ...de matériaux et couleurs - 5 = Blanc; ...de stratigraphies = Placoplâtre standard en plaques de 13
Faux-plafond 152175 | Niveau 2 | 152175 | 2 | 106 | -746779066 | 52 | 05 | Niveau 2 | HAUT Niveau 2 (Mezzanine 49003) | -26 | 6261 | 1643 | 7904 | 483500 | 74500 | 558000 | 558001 | 558001 | ...de matériaux et couleurs = Blanc; ...de matériaux et couleurs - 1 = Blanc; ...de matériaux et couleurs - 2 = Blanc; ...de matériaux et couleurs - 6 = Blanc; ...de matériaux et couleurs - 7 = Blanc; ...de matériaux et couleurs - 3 = Blanc; ...de matériaux et couleurs - 4 = Blanc; ...de matériaux et couleurs - 5 = Blanc; ...de stratigraphies = Placoplâtre standard en plaques de 13; ...de matériaux et couleurs - 8 = Blanc; ...de matériaux et couleurs - 9 = Blanc; ...de matériaux et couleurs - 10 = Blanc; ...de matériaux et couleurs - 11 = Blanc; ...de matériaux et couleurs - 12 = Blanc; ...de matériaux et couleurs - 13 = Blanc; ...de matériaux et couleurs - 14 = Blanc; ...de matériaux et couleurs - 15 = Blanc; ...de matériaux et couleurs - 16 = Blanc; ...de stratigraphies - 1 = Placoplâtre standard en plaques de 13; ...de stratigraphies - 2 = Placoplâtre standard en plaques de 13; ...de matériaux et couleurs - 17 = Blanc; ...de matériaux et couleurs - 18 = Blanc; ...de matériaux et couleurs - 19 = Blanc; ...de matériaux et couleurs - 20 = Blanc; ...de matériaux et couleurs - 21 = Blanc; ...de matériaux et couleurs - 22 = Blanc; ...de matériaux et couleurs - 23 = Blanc; ...de stratigraphies - 3 = Placoplâtre standard en plaques de 13; ...de stratigraphies - 4 = Placoplâtre standard en plaques de 10; ...de stratigraphies - 5 = Placoplâtre standard en plaques de 10; ...de stratigraphies - 6 = Placoplâtre standard en plaques de 10 | CTLG_EXTERNAL_LINK - 7, DocType: 2; 7, Tag: 107; 7, Crc: -746779066; 8, DocType: 2; 8, Tag: 108; 8, Crc: -746779066; 9, DocType: 2; 9, Tag: 109; 9, Crc: -746779066; 10, DocType: 2; 10, Tag: 110; 10, Crc: -746779066; 11, DocType: 2; 11, Tag: 111; 11, Crc: -746779066; 12, DocType: 2; 12, Tag: 112; 12, Crc: -746779066; 13, DocType: 2; 13, Tag: 113; 13, Crc: -746779066; 14, DocType: 2; 14, Tag: 114; 14, Crc: -746779066; 15, DocType: 2; 15, Tag: 115; 15, Crc: -746779066; 16, DocType: 2; 16, Tag: 116; 16, Crc: -746779066; 17, DocType: 2; 17, Tag: 117; 17, Crc: -746779066; 18, DocType: 2; 18, Tag: 118; 18, Crc: -746779066; 19, DocType: 2; 19, Tag: 119; 19, Crc: -746779066; 20, DocType: 2; 20, Tag: 120; 20, Crc: -746779066; 21, DocType: 2; 21, Tag: 121; 21, Crc: -746779066; 22, DocType: 2; 22, Tag: 122; 22, Crc: -746779066; 23, DocType: 2; 23, Tag: 123; 23, Crc: -746779066; 24, DocType: 9; 24, Tag: 101; 24, Crc: -2060481618; 25, DocType: 9; 25, Tag: 102; 25, Crc: -2060481618; 26, DocType: 9; 26, Tag: 103; 26, Crc: -2060481618; 27, DocType: 9; 27, Tag: 104; 27, Crc: -2060481618; 28, DocType: 9; 28, Tag: 105; 28, Crc: 1896997855; 29, DocType: 9; 29, Tag: 106; 29, Crc: 1896997855; 30, DocType: 9; 30, Tag: 107; 30, Crc: 1896997855
Faux-plafond 152971 | Niveau 2 | 152971 | 2 | 106 | -746779066 | 53 | 05 | Niveau 2 | HAUT Niveau 2 (Mezzanine 49003) | 5 | 3656 | 549 | 4205 | 386900 | 16500 | 403300 | 403326 | 403326 | ...de matériaux et couleurs = Blanc; ...de matériaux et couleurs - 1 = Blanc; ...de matériaux et couleurs - 2 = Blanc; ...de matériaux et couleurs - 6 = Blanc; ...de matériaux et couleurs - 7 = Blanc; ...de matériaux et couleurs - 3 = Blanc; ...de matériaux et couleurs - 4 = Blanc; ...de matériaux et couleurs - 5 = Blanc; ...de stratigraphies = Placoplâtre standard en plaques de 13; ...de matériaux et couleurs - 8 = Blanc; ...de matériaux et couleurs - 9 = Blanc; ...de matériaux et couleurs - 10 = Blanc; ...de matériaux et couleurs - 11 = Blanc; ...de stratigraphies - 1 = Placoplâtre standard en plaques de 13; ...de stratigraphies - 2 = Placoplâtre standard en plaques de 10 | CTLG_EXTERNAL_LINK - 7, DocType: 2; 7, Tag: 107; 7, Crc: -746779066; 8, DocType: 2; 8, Tag: 108; 8, Crc: -746779066; 9, DocType: 2; 9, Tag: 109; 9, Crc: -746779066; 10, DocType: 2; 10, Tag: 110; 10, Crc: -746779066; 11, DocType: 2; 11, Tag: 111; 11, Crc: -746779066; 12, DocType: 9; 12, Tag: 101; 12, Crc: -2060481618; 13, DocType: 9; 13, Tag: 102; 13, Crc: -2060481618; 14, DocType: 9; 14, Tag: 103; 14, Crc: 1896997855
Faux-plafond 152116 | Niveau 2 | 152116 | 9 | 101 | -2060481618 | 50 | 05 | Niveau 2 | HAUT Niveau 2 (Mezzanine 49003) | -27.5 | 537 | 0 | 537 | 17500 | 0 | 17500 | 17541.5 | 17541.5 | ...de matériaux et couleurs = Blanc; ...de matériaux et couleurs - 1 = Blanc; ...de matériaux et couleurs - 2 = Blanc; ...de matériaux et couleurs - 3 = Blanc; ...de matériaux et couleurs - 4 = Blanc; ...de matériaux et couleurs - 5 = Blanc; ...de stratigraphies = Placoplâtre standard en plaques de 13
Faux-plafond 152117 | Niveau 2 | 152117 | 9 | 101 | -2060481618 | 51 | 05 | Niveau 2 | HAUT Niveau 2 (Mezzanine 49003) | -26 | 713 | 0 | 713 | 31200 | 0 | 31200 | 31200.4 | 31200.4 | ...de matériaux et couleurs = Blanc; ...de matériaux et couleurs - 1 = Blanc; ...de matériaux et couleurs - 2 = Blanc; ...de matériaux et couleurs - 3 = Blanc; ...de matériaux et couleurs - 4 = Blanc; ...de matériaux et couleurs - 5 = Blanc; ...de stratigraphies = Placoplâtre standard en plaques de 13
Faux-plafond 170647 | Niveau 2 | 170647 | 9 | 101 | -2060481618 | 54 | 05 | Niveau 2 | HAUT Niveau 2 (Mezzanine 49003) | -16.5 | 448 | 0 | 448 | 12500 | 0 | 12500 | 12526 | 12526 | ...de matériaux et couleurs = Blanc; ...de matériaux et couleurs - 1 = Blanc; ...de matériaux et couleurs - 2 = Blanc; ...de matériaux et couleurs - 3 = Blanc; ...de matériaux et couleurs - 4 = Blanc; ...de matériaux et couleurs - 5 = Blanc; ...de stratigraphies = Placoplâtre standard en plaques de 13
Faux-plafond 724694 | Niveau 2 | 724694 | 2 | 106 | -746779066 | 63 | 05 | Niveau 2 | HAUT Niveau 2 (Mezzanine 49003) | -20 | 3343 | 1030 | 4373 | 506600 | 28400 | 535000 | 535017 | 303781 | ...de matériaux et couleurs = Blanc; ...de matériaux et couleurs - 1 = Blanc; ...de matériaux et couleurs - 2 = Blanc; ...de matériaux et couleurs - 6 = Blanc; ...de matériaux et couleurs - 3 = Blanc; ...de matériaux et couleurs - 4 = Blanc; ...de matériaux et couleurs - 5 = Blanc; ...de stratigraphies = Placoplâtre standard en plaques de 13; ...de stratigraphies - 1 = Placoplâtre standard en plaques de 10 | CTLG_EXTERNAL_LINK - 7, DocType: 9; 7, Tag: 101; 7, Crc: -2060481618; 8, DocType: 9; 8, Tag: 102; 8, Crc: 1896997855
Faux-plafond 206070 | Niveau 2 | 206070 | 9 | 101 | -2060481618 | 58 | 05 | Niveau 2 | HAUT Niveau 2 (Mezzanine 49003) | 12.5 | 1971 | 0 | 1971 | 242900 | 0 | 242900 | 242902 | 242902 | ...de matériaux et couleurs = Blanc; ...de matériaux et couleurs - 1 = Blanc; ...de matériaux et couleurs - 2 = Blanc; ...de matériaux et couleurs - 3 = Blanc; ...de matériaux et couleurs - 4 = Blanc; ...de matériaux et couleurs - 5 = Blanc; ...de stratigraphies = Placoplâtre standard en plaques de 13
Faux-plafond 176923 | Niveau 2 | 176923 | 2 | 106 | -746779066 | 55 | 05 | Niveau 2 | HAUT Niveau 2 (Mezzanine 49003) | -13 | 2589 | 191 | 2780 | 192600 | 1100 | 193700 | 193684 | 193684 | ...de matériaux et couleurs = Blanc; ...de matériaux et couleurs - 1 = Blanc; ...de matériaux et couleurs - 2 = Blanc; ...de matériaux et couleurs - 6 = Blanc; ...de matériaux et couleurs - 7 = Blanc; ...de matériaux et couleurs - 3 = Blanc; ...de matériaux et couleurs - 4 = Blanc; ...de matériaux et couleurs - 5 = Blanc; ...de stratigraphies = Placoplâtre standard en plaques de 13; ...de matériaux et couleurs - 8 = Blanc; ...de matériaux et couleurs - 9 = Blanc; ...de matériaux et couleurs - 10 = Blanc; ...de matériaux et couleurs - 11 = Blanc; ...de stratigraphies - 1 = Placoplâtre standard en plaques de 13; ...de stratigraphies - 2 = Placoplâtre standard en plaques de 10 | CTLG_EXTERNAL_LINK - 7, DocType: 2; 7, Tag: 107; 7, Crc: -746779066; 8, DocType: 2; 8, Tag: 108; 8, Crc: -746779066; 9, DocType: 2; 9, Tag: 109; 9, Crc: -746779066; 10, DocType: 2; 10, Tag: 110; 10, Crc: -746779066; 11, DocType: 2; 11, Tag: 111; 11, Crc: -746779066; 12, DocType: 9; 12, Tag: 101; 12, Crc: -2060481618; 13, DocType: 9; 13, Tag: 102; 13, Crc: -2060481618; 14, DocType: 9; 14, Tag: 103; 14, Crc: 1896997855
Faux-plafond 564891 | Niveau 2 | 564891 | 9 | 101 | -2060481618 | 62 | 05 | Niveau 2 | HAUT Niveau 2 (Mezzanine 49003) | -20 | 3207 | 0 | 3207 | 485400 | 0 | 485400 | 485421 | 252324 | ...de matériaux et couleurs = Blanc; ...de matériaux et couleurs - 1 = Blanc; ...de matériaux et couleurs - 2 = Blanc; ...de matériaux et couleurs - 3 = Blanc; ...de matériaux et couleurs - 4 = Blanc; ...de matériaux et couleurs - 5 = Blanc; ...de stratigraphies = Placoplâtre standard en plaques de 13
Faux-plafond 206400 | Niveau 2 | 206400 | 9 | 101 | -2060481618 | 59 | 05 | Niveau 2 | HAUT Niveau 2 (Mezzanine 49003) | -10 | 1037 | 0 | 1037 | 49000 | 0 | 49000 | 49022.5 | 49022.5 | ...de matériaux et couleurs = Blanc; ...de matériaux et couleurs - 1 = Blanc; ...de matériaux et couleurs - 2 = Blanc; ...de matériaux et couleurs - 3 = Blanc; ...de matériaux et couleurs - 4 = Blanc; ...de matériaux et couleurs - 5 = Blanc; ...de stratigraphies = Placoplâtre standard en plaques de 13
Faux-plafond 219732 | Niveau 2 | 219732 | 9 | 101 | -2060481618 | 60 | 05 | Niveau 2 | HAUT Niveau 2 (Mezzanine 49003) | -25.5 | 2703 | 0 | 2703 | 295200 | 0 | 295200 | 295216 | 295216 | ...de matériaux et couleurs = Blanc; ...de matériaux et couleurs - 1 = Blanc; ...de matériaux et couleurs - 2 = Blanc; ...de matériaux et couleurs - 3 = Blanc; ...de matériaux et couleurs - 4 = Blanc; ...de matériaux et couleurs - 5 = Blanc; ...de stratigraphies = Placoplâtre standard en plaques de 13
Faux-plafond 1872883 | Mezzanine | 1872883 | 9 | 101 | -2060481618 | 66 | 06 | Mezzanine | HAUT Mezzanine (Couverture 2134) | -28 | 1145 | 0 | 1145 | 65100 | 0 | 65100 | 65067.6 | 65067.6 | ...de matériaux et couleurs = Blanc; ...de matériaux et couleurs - 1 = Blanc; ...de matériaux et couleurs - 2 = Blanc; ...de matériaux et couleurs - 3 = Blanc; ...de matériaux et couleurs - 4 = Blanc; ...de matériaux et couleurs - 5 = Blanc; ...de stratigraphies = Placoplâtre standard en plaques de 13
Faux-plafond 1896586 | Mezzanine | 1896586 | 2 | 106 | -746779066 | 67 | 06 | Mezzanine | HAUT Mezzanine (Couverture 2134) | -25 | 3698 | 0 | 3698 | 302500 | 0 | 302500 | 302531 | 302531 | ...de matériaux et couleurs = Blanc; ...de matériaux et couleurs - 1 = Blanc; ...de matériaux et couleurs - 2 = Blanc; ...de matériaux et couleurs - 6 = Blanc; ...de matériaux et couleurs - 7 = Blanc; ...de matériaux et couleurs - 3 = Blanc; ...de matériaux et couleurs - 4 = Blanc; ...de matériaux et couleurs - 5 = Blanc; ...de stratigraphies = Placoplâtre standard en plaques de 13; ...de matériaux et couleurs - 8 = Blanc; ...de matériaux et couleurs - 9 = Blanc; ...de matériaux et couleurs - 10 = Blanc; ...de stratigraphies - 1 = Placoplâtre standard en plaques de 13 | CTLG_EXTERNAL_LINK - 7, DocType: 2; 7, Tag: 107; 7, Crc: -746779066; 8, DocType: 2; 8, Tag: 108; 8, Crc: -746779066; 9, DocType: 2; 9, Tag: 109; 9, Crc: -746779066; 10, DocType: 2; 10, Tag: 110; 10, Crc: -746779066; 11, DocType: 9; 11, Tag: 101; 11, Crc: -2060481618; 12, DocType: 9; 12, Tag: 102; 12, Crc: -2060481618
Faux-plafond 1779083 | Mezzanine | 1779083 | 2 | 106 | -746779066 | 64 | 06 | Mezzanine | HAUT Mezzanine (Couverture 2134) | 0 | 2408 | 0 | 2408 | 93700 | 0 | 93700 | 93717.7 | 93717.7 | ...de matériaux et couleurs = Blanc; ...de matériaux et couleurs - 1 = Blanc; ...de matériaux et couleurs - 2 = Blanc; ...de matériaux et couleurs - 6 = Blanc; ...de matériaux et couleurs - 7 = Blanc; ...de matériaux et couleurs - 3 = Blanc; ...de matériaux et couleurs - 4 = Blanc; ...de matériaux et couleurs - 5 = Blanc; ...de stratigraphies = Placoplâtre standard en plaques de 13; ...de matériaux et couleurs - 8 = Blanc; ...de matériaux et couleurs - 9 = Blanc; ...de matériaux et couleurs - 10 = Blanc; ...de matériaux et couleurs - 11 = Blanc; ...de matériaux et couleurs - 12 = Blanc; ...de matériaux et couleurs - 13 = Blanc; ...de matériaux et couleurs - 14 = Blanc; ...de matériaux et couleurs - 15 = Blanc; ...de stratigraphies - 1 = Placoplâtre standard en plaques de 13; ...de stratigraphies - 2 = Placoplâtre standard en plaques de 13 | CTLG_EXTERNAL_LINK - 7, DocType: 2; 7, Tag: 107; 7, Crc: -746779066; 8, DocType: 2; 8, Tag: 108; 8, Crc: -746779066; 9, DocType: 2; 9, Tag: 109; 9, Crc: -746779066; 10, DocType: 2; 10, Tag: 110; 10, Crc: -746779066; 11, DocType: 2; 11, Tag: 111; 11, Crc: -746779066; 12, DocType: 2; 12, Tag: 112; 12, Crc: -746779066; 13, DocType: 2; 13, Tag: 113; 13, Crc: -746779066; 14, DocType: 2; 14, Tag: 114; 14, Crc: -746779066; 15, DocType: 2; 15, Tag: 115; 15, Crc: -746779066; 16, DocType: 9; 16, Tag: 101; 16, Crc: -2060481618; 17, DocType: 9; 17, Tag: 102; 17, Crc: -2060481618; 18, DocType: 9; 18, Tag: 103; 18, Crc: -2060481618
Faux-plafond 1780555 | Mezzanine | 1780555 | 9 | 101 | -2060481618 | 65 | 06 | Mezzanine | HAUT Mezzanine (Couverture 2134) | 0 | 1228 | 0 | 1228 | 89700 | 0 | 89700 | 89685.9 | 89685.9 | ...de matériaux et couleurs = Blanc; ...de matériaux et couleurs - 1 = Blanc; ...de matériaux et couleurs - 2 = Blanc; ...de matériaux et couleurs - 3 = Blanc; ...de matériaux et couleurs - 4 = Blanc; ...de matériaux et couleurs - 5 = Blanc; ...de stratigraphies = Placoplâtre standard en plaques de 13
Faux-plafond 1900155 | Mezzanine | 1900155 | 2 | 106 | -746779066 | 70 | 06 | Mezzanine | HAUT Mezzanine (Couverture 2134) | -65 | 2203 | 0 | 2203 | 126500 | 0 | 126500 | 126459 | 126459 | ...de matériaux et couleurs = Blanc; ...de matériaux et couleurs - 1 = Blanc; ...de matériaux et couleurs - 2 = Blanc; ...de matériaux et couleurs - 6 = Blanc; ...de matériaux et couleurs - 7 = Blanc; ...de matériaux et couleurs - 3 = Blanc; ...de matériaux et couleurs - 4 = Blanc; ...de matériaux et couleurs - 5 = Blanc; ...de stratigraphies = Placoplâtre standard en plaques de 13; ...de matériaux et couleurs - 8 = Blanc; ...de matériaux et couleurs - 9 = Blanc; ...de matériaux et couleurs - 10 = Blanc; ...de stratigraphies - 1 = Placoplâtre standard en plaques de 13 | CTLG_EXTERNAL_LINK - 7, DocType: 2; 7, Tag: 107; 7, Crc: -746779066; 8, DocType: 2; 8, Tag: 108; 8, Crc: -746779066; 9, DocType: 2; 9, Tag: 109; 9, Crc: -746779066; 10, DocType: 2; 10, Tag: 110; 10, Crc: -746779066; 11, DocType: 9; 11, Tag: 101; 11, Crc: -2060481618; 12, DocType: 9; 12, Tag: 102; 12, Crc: -2060481618
Faux-plafond 1900156 | Mezzanine | 1900156 | 2 | 106 | -746779066 | 71 | 06 | Mezzanine | HAUT Mezzanine (Couverture 2134) | -14.0928 | 11490 | 0 | 11490 | 1135100 | 0 | 1135100 | 1135146 | 1113208 | ...de matériaux et couleurs = Blanc; ...de matériaux et couleurs - 1 = Blanc; ...de matériaux et couleurs - 2 = Blanc; ...de matériaux et couleurs - 6 = Blanc; ...de matériaux et couleurs - 7 = Blanc; ...de matériaux et couleurs - 3 = Blanc; ...de matériaux et couleurs - 4 = Blanc; ...de matériaux et couleurs - 5 = Blanc; ...de stratigraphies = Placoplâtre standard en plaques de 13; ...de matériaux et couleurs - 8 = Blanc; ...de matériaux et couleurs - 9 = Blanc; ...de matériaux et couleurs - 10 = Blanc; ...de matériaux et couleurs - 11 = Blanc; ...de matériaux et couleurs - 12 = Blanc; ...de matériaux et couleurs - 13 = Blanc; ...de matériaux et couleurs - 14 = Blanc; ...de matériaux et couleurs - 15 = Blanc; ...de matériaux et couleurs - 16 = Blanc; ...de stratigraphies - 1 = Placoplâtre standard en plaques de 13; ...de stratigraphies - 2 = Placoplâtre standard en plaques de 13; ...de matériaux et couleurs - 17 = Blanc; ...de matériaux et couleurs - 18 = Blanc; ...de matériaux et couleurs - 19 = Blanc; ...de matériaux et couleurs - 20 = Blanc; ...de stratigraphies - 3 = Placoplâtre standard en plaques de 13 | CTLG_EXTERNAL_LINK - 7, DocType: 2; 7, Tag: 107; 7, Crc: -746779066; 8, DocType: 2; 8, Tag: 108; 8, Crc: -746779066; 9, DocType: 2; 9, Tag: 109; 9, Crc: -746779066; 10, DocType: 2; 10, Tag: 110; 10, Crc: -746779066; 11, DocType: 2; 11, Tag: 111; 11, Crc: -746779066; 12, DocType: 2; 12, Tag: 112; 12, Crc: -746779066; 13, DocType: 2; 13, Tag: 113; 13, Crc: -746779066; 14, DocType: 2; 14, Tag: 114; 14, Crc: -746779066; 15, DocType: 2; 15, Tag: 115; 15, Crc: -746779066; 16, DocType: 2; 16, Tag: 116; 16, Crc: -746779066; 17, DocType: 2; 17, Tag: 117; 17, Crc: -746779066; 18, DocType: 2; 18, Tag: 118; 18, Crc: -746779066; 19, DocType: 2; 19, Tag: 119; 19, Crc: -746779066; 20, DocType: 2; 20, Tag: 120; 20, Crc: -746779066; 21, DocType: 9; 21, Tag: 101; 21, Crc: -2060481618; 22, DocType: 9; 22, Tag: 102; 22, Crc: -2060481618; 23, DocType: 9; 23, Tag: 103; 23, Crc: -2060481618; 24, DocType: 9; 24, Tag: 104; 24, Crc: -2060481618
Faux-plafond 1900119 | Mezzanine | 1900119 | 2 | 106 | -746779066 | 68 | 06 | Mezzanine | HAUT Mezzanine (Couverture 2134) | -47 | 1566 | 0 | 1566 | 28800 | 0 | 28800 | 28763.6 | 28763.6 | ...de matériaux et couleurs = Blanc; ...de matériaux et couleurs - 1 = Blanc; ...de matériaux et couleurs - 2 = Blanc; ...de matériaux et couleurs - 6 = Blanc; ...de matériaux et couleurs - 7 = Blanc; ...de matériaux et couleurs - 3 = Blanc; ...de matériaux et couleurs - 4 = Blanc; ...de matériaux et couleurs - 5 = Blanc; ...de stratigraphies = Placoplâtre standard en plaques de 13; ...de matériaux et couleurs - 8 = Blanc; ...de matériaux et couleurs - 9 = Blanc; ...de matériaux et couleurs - 10 = Blanc; ...de matériaux et couleurs - 11 = Blanc; ...de matériaux et couleurs - 12 = Blanc; ...de matériaux et couleurs - 13 = Blanc; ...de matériaux et couleurs - 14 = Blanc; ...de matériaux et couleurs - 15 = Blanc; ...de matériaux et couleurs - 16 = Blanc; ...de stratigraphies - 1 = Placoplâtre standard en plaques de 13; ...de stratigraphies - 2 = Placoplâtre standard en plaques de 13; ...de matériaux et couleurs - 17 = Blanc; ...de matériaux et couleurs - 18 = Blanc; ...de matériaux et couleurs - 19 = Blanc; ...de matériaux et couleurs - 20 = Blanc; ...de matériaux et couleurs - 21 = Blanc; ...de matériaux et couleurs - 22 = Blanc; ...de matériaux et couleurs - 23 = Blanc; ...de stratigraphies - 3 = Placoplâtre standard en plaques de 13; ...de matériaux et couleurs - 24 = Blanc; ...de matériaux et couleurs - 25 = Blanc; ...de stratigraphies - 4 = Placoplâtre standard en plaques de 13 | CTLG_EXTERNAL_LINK - 7, DocType: 2; 7, Tag: 107; 7, Crc: -746779066; 8, DocType: 2; 8, Tag: 108; 8, Crc: -746779066; 9, DocType: 2; 9, Tag: 109; 9, Crc: -746779066; 10, DocType: 2; 10, Tag: 110; 10, Crc: -746779066; 11, DocType: 2; 11, Tag: 111; 11, Crc: -746779066; 12, DocType: 2; 12, Tag: 112; 12, Crc: -746779066; 13, DocType: 2; 13, Tag: 113; 13, Crc: -746779066; 14, DocType: 2; 14, Tag: 114; 14, Crc: -746779066; 15, DocType: 2; 15, Tag: 115; 15, Crc: -746779066; 16, DocType: 2; 16, Tag: 116; 16, Crc: -746779066; 17, DocType: 2; 17, Tag: 117; 17, Crc: -746779066; 18, DocType: 2; 18, Tag: 118; 18, Crc: -746779066; 19, DocType: 2; 19, Tag: 119; 19, Crc: -746779066; 20, DocType: 2; 20, Tag: 120; 20, Crc: -746779066; 21, DocType: 2; 21, Tag: 121; 21, Crc: -746779066; 22, DocType: 2; 22, Tag: 122; 22, Crc: -746779066; 23, DocType: 2; 23, Tag: 123; 23, Crc: -746779066; 24, DocType: 2; 24, Tag: 124; 24, Crc: -746779066; 25, DocType: 2; 25, Tag: 125; 25, Crc: -746779066; 26, DocType: 9; 26, Tag: 101; 26, Crc: -2060481618; 27, DocType: 9; 27, Tag: 102; 27, Crc: -2060481618; 28, DocType: 9; 28, Tag: 103; 28, Crc: -2060481618; 29, DocType: 9; 29, Tag: 104; 29, Crc: -2060481618; 30, DocType: 9; 30, Tag: 105; 30, Crc: -2060481618
Faux-plafond 1900120 | Mezzanine | 1900120 | 2 | 106 | -746779066 | 69 | 06 | Mezzanine | HAUT Mezzanine (Couverture 2134) | -64 | 1452 | 0 | 1452 | 34000 | 0 | 34000 | 33998.5 | 33998.5 | ...de matériaux et couleurs = Blanc; ...de matériaux et couleurs - 1 = Blanc; ...de matériaux et couleurs - 2 = Blanc; ...de matériaux et couleurs - 6 = Blanc; ...de matériaux et couleurs - 7 = Blanc; ...de matériaux et couleurs - 3 = Blanc; ...de matériaux et couleurs - 4 = Blanc; ...de matériaux et couleurs - 5 = Blanc; ...de stratigraphies = Placoplâtre standard en plaques de 13; ...de matériaux et couleurs - 8 = Blanc; ...de matériaux et couleurs - 9 = Blanc; ...de matériaux et couleurs - 10 = Blanc; ...de stratigraphies - 1 = Placoplâtre standard en plaques de 13 | CTLG_EXTERNAL_LINK - 7, DocType: 2; 7, Tag: 107; 7, Crc: -746779066; 8, DocType: 2; 8, Tag: 108; 8, Crc: -746779066; 9, DocType: 2; 9, Tag: 109; 9, Crc: -746779066; 10, DocType: 2; 10, Tag: 110; 10, Crc: -746779066; 11, DocType: 9; 11, Tag: 101; 11, Crc: -2060481618; 12, DocType: 9; 12, Tag: 102; 12, Crc: -2060481618
Faux-plafond 200767 | Mezzanine | 200767 | 2 | 106 | -746779066 | 57 | 06 | Mezzanine | HAUT Mezzanine (Couverture 2134) | -68 | 5622 | 0 | 5622 | 301300 | 0 | 301300 | 301343 | 301343 | ...de matériaux et couleurs = Blanc; ...de matériaux et couleurs - 1 = Blanc; ...de matériaux et couleurs - 2 = Blanc; ...de matériaux et couleurs - 6 = Blanc; ...de matériaux et couleurs - 7 = Blanc; ...de matériaux et couleurs - 3 = Blanc; ...de matériaux et couleurs - 4 = Blanc; ...de matériaux et couleurs - 5 = Blanc; ...de stratigraphies = Placoplâtre standard en plaques de 13; ...de matériaux et couleurs - 8 = Blanc; ...de matériaux et couleurs - 9 = Blanc; ...de matériaux et couleurs - 10 = Blanc; ...de matériaux et couleurs - 11 = Blanc; ...de matériaux et couleurs - 12 = Blanc; ...de matériaux et couleurs - 13 = Blanc; ...de matériaux et couleurs - 14 = Blanc; ...de matériaux et couleurs - 15 = Blanc; ...de matériaux et couleurs - 16 = Blanc; ...de stratigraphies - 1 = Placoplâtre standard en plaques de 13; ...de stratigraphies - 2 = Placoplâtre standard en plaques de 13; ...de matériaux et couleurs - 17 = Blanc; ...de matériaux et couleurs - 18 = Blanc; ...de matériaux et couleurs - 19 = Blanc; ...de matériaux et couleurs - 20 = Blanc; ...de matériaux et couleurs - 21 = Blanc; ...de matériaux et couleurs - 22 = Blanc; ...de matériaux et couleurs - 23 = Blanc; ...de stratigraphies - 3 = Placoplâtre standard en plaques de 13; ...de matériaux et couleurs - 24 = Blanc; ...de matériaux et couleurs - 25 = Blanc; ...de stratigraphies - 4 = Placoplâtre standard en plaques de 13 | CTLG_EXTERNAL_LINK - 7, DocType: 2; 7, Tag: 107; 7, Crc: -746779066; 8, DocType: 2; 8, Tag: 108; 8, Crc: -746779066; 9, DocType: 2; 9, Tag: 109; 9, Crc: -746779066; 10, DocType: 2; 10, Tag: 110; 10, Crc: -746779066; 11, DocType: 2; 11, Tag: 111; 11, Crc: -746779066; 12, DocType: 2; 12, Tag: 112; 12, Crc: -746779066; 13, DocType: 2; 13, Tag: 113; 13, Crc: -746779066; 14, DocType: 2; 14, Tag: 114; 14, Crc: -746779066; 15, DocType: 2; 15, Tag: 115; 15, Crc: -746779066; 16, DocType: 2; 16, Tag: 116; 16, Crc: -746779066; 17, DocType: 2; 17, Tag: 117; 17, Crc: -746779066; 18, DocType: 2; 18, Tag: 118; 18, Crc: -746779066; 19, DocType: 2; 19, Tag: 119; 19, Crc: -746779066; 20, DocType: 2; 20, Tag: 120; 20, Crc: -746779066; 21, DocType: 2; 21, Tag: 121; 21, Crc: -746779066; 22, DocType: 2; 22, Tag: 122; 22, Crc: -746779066; 23, DocType: 2; 23, Tag: 123; 23, Crc: -746779066; 24, DocType: 2; 24, Tag: 124; 24, Crc: -746779066; 25, DocType: 2; 25, Tag: 125; 25, Crc: -746779066; 26, DocType: 9; 26, Tag: 101; 26, Crc: -2060481618; 27, DocType: 9; 27, Tag: 102; 27, Crc: -2060481618; 28, DocType: 9; 28, Tag: 103; 28, Crc: -2060481618; 29, DocType: 9; 29, Tag: 104; 29, Crc: -2060481618; 30, DocType: 9; 30, Tag: 105; 30, Crc: -2060481618
Faux-plafond 193151 | Mezzanine | 193151 | 2 | 106 | -746779066 | 56 | 06 | Mezzanine | HAUT Mezzanine (Couverture 2134) | 0 | 5716 | 0 | 5716 | 352600 | 0 | 352600 | 352643 | 340728 | ...de matériaux et couleurs = Blanc; ...de matériaux et couleurs - 1 = Blanc; ...de matériaux et couleurs - 2 = Blanc; ...de matériaux et couleurs - 6 = Blanc; ...de matériaux et couleurs - 7 = Blanc; ...de matériaux et couleurs - 3 = Blanc; ...de matériaux et couleurs - 4 = Blanc; ...de matériaux et couleurs - 5 = Blanc; ...de stratigraphies = Placoplâtre standard en plaques de 13; ...de matériaux et couleurs - 8 = Blanc; ...de matériaux et couleurs - 9 = Blanc; ...de matériaux et couleurs - 10 = Blanc; ...de matériaux et couleurs - 11 = Blanc; ...de matériaux et couleurs - 12 = Blanc; ...de matériaux et couleurs - 13 = Blanc; ...de matériaux et couleurs - 14 = Blanc; ...de matériaux et couleurs - 15 = Blanc; ...de matériaux et couleurs - 16 = Blanc; ...de stratigraphies - 1 = Placoplâtre standard en plaques de 13; ...de stratigraphies - 2 = Placoplâtre standard en plaques de 13; ...de matériaux et couleurs - 17 = Blanc; ...de matériaux et couleurs - 18 = Blanc; ...de matériaux et couleurs - 19 = Blanc; ...de matériaux et couleurs - 20 = Blanc; ...de matériaux et couleurs - 21 = Blanc; ...de matériaux et couleurs - 22 = Blanc; ...de matériaux et couleurs - 23 = Blanc; ...de stratigraphies - 3 = Placoplâtre standard en plaques de 13; ...de matériaux et couleurs - 24 = Blanc; ...de matériaux et couleurs - 25 = Blanc; ...de stratigraphies - 4 = Placoplâtre standard en plaques de 13 | CTLG_EXTERNAL_LINK - 7, DocType: 2; 7, Tag: 107; 7, Crc: -746779066; 8, DocType: 2; 8, Tag: 108; 8, Crc: -746779066; 9, DocType: 2; 9, Tag: 109; 9, Crc: -746779066; 10, DocType: 2; 10, Tag: 110; 10, Crc: -746779066; 11, DocType: 2; 11, Tag: 111; 11, Crc: -746779066; 12, DocType: 2; 12, Tag: 112; 12, Crc: -746779066; 13, DocType: 2; 13, Tag: 113; 13, Crc: -746779066; 14, DocType: 2; 14, Tag: 114; 14, Crc: -746779066; 15, DocType: 2; 15, Tag: 115; 15, Crc: -746779066; 16, DocType: 2; 16, Tag: 116; 16, Crc: -746779066; 17, DocType: 2; 17, Tag: 117; 17, Crc: -746779066; 18, DocType: 2; 18, Tag: 118; 18, Crc: -746779066; 19, DocType: 2; 19, Tag: 119; 19, Crc: -746779066; 20, DocType: 2; 20, Tag: 120; 20, Crc: -746779066; 21, DocType: 2; 21, Tag: 121; 21, Crc: -746779066; 22, DocType: 2; 22, Tag: 122; 22, Crc: -746779066; 23, DocType: 2; 23, Tag: 123; 23, Crc: -746779066; 24, DocType: 2; 24, Tag: 124; 24, Crc: -746779066; 25, DocType: 2; 25, Tag: 125; 25, Crc: -746779066; 26, DocType: 9; 26, Tag: 101; 26, Crc: -2060481618; 27, DocType: 9; 27, Tag: 102; 27, Crc: -2060481618; 28, DocType: 9; 28, Tag: 103; 28, Crc: -2060481618; 29, DocType: 9; 29, Tag: 104; 29, Crc: -2060481618; 30, DocType: 9; 30, Tag: 105; 30, Crc: -2060481618

# IfcDoor: Porte de Secours_1VB[1P plein]_IMP arc (2)
In: Rez-de-Jardin
Type - ParameterTakesPrecedence: no; Sizeable: no; Material: Aluminium satiné, Blanc trafic
Type - IfcDoorLiningProperties - LiningDepth: 8 cm; LiningThickness: 3 cm
Description: Porte
__RECOGNIZE__ - TPLG: 102; TPLG_OD: 9005; GENERATE: 1
CTLG_EXTERNAL_LINK - 0, DocType: 3; 0, Tag: 100; 0, Crc: -987826624; 1, DocType: 2; 1, Tag: 0; 1, Crc: -746779066; 2, DocType: 2; 2, Tag: 102; 2, Crc: -848491367; 3, DocType: 2; 3, Tag: 105; 3, Crc: -848491367; 4, DocType: 2; 4, Tag: 107; 4, Crc: 1305662025
IFC_PSET_PolygonOffset - polygonOffsetFactor: 2; polygonOffsetUnits: 2
IFC_Pset_Caractéristiques - Numéro niveau: 02; Titre niveau: Rez-de-Jardin; Modèle 1re menuiserie: Porte de Secours_1VB[1P plein]_IMP arc
IFC_Pset_Géométrie_Ébrasement - Côté supérieur: no; Côté INFÉRIEUR: no; Épaisseur latérale gauche: 0 cm; Épaisseur latérale droite: 0 cm; Épiasseur latérale supérieure: 0 cm; Épaisseur intérieur: 0 cm
IFC_Pset_Géométrie_Seuil - Type: Aucun; Épaisseur: 0 cm; Épaisseur interne: 0 cm; Décalage séparation: 0 cm; Appui extérieur: 0 cm; Appui intérieur: 0 cm; Côté latéral externe: 0 cm; Côté latéral interne: 0 cm
IFC_Pset_Géométrie_Chambranle - Position: Aucun; Épaisseur Chambranle intérieur: 0 cm; Longueur Chambranle intérieur: 0 cm; Superposition Chambranle intérieur: 0 cm; Épaisseur Intrados: 0 cm; Épaisseur Chambranle extérieur: 0 cm; Largeur Chambranle extérieur: 0 cm; Superposition Chambranle extérieur: 0 cm; Épaisseur Intrados extérieur: 0 cm
IFC_Pset_Géométrie_CORNICHE depuis profil - Position: Aucune; sets with these values: 2
IFC_Pset_Géométrie_CORNICHE Extérieure à partir d'un profil - Décalage: 0; Angle: 0 deg; Symétrie: no; Fermer: no; sets with these values: 2
IFC_Pset_Géométrie_BASE Extérieure à partir d'un profil - Angle: 0 deg; Symétrie: no; Côté: 0 cm; sets with these values: 2
IFC_Pset_Géométrie_1° MENUISERIE - Position: Intérieur
IFC_Pset_Géométrie_2° MENUISERIE - Décalage: 0 cm
IFC_Pset_Géométrie - Invertir (dte/gche): yes; Invertir (intérieur/extérieur): yes; Hauteur 2: 0 cm; Rayon Cercle: 0 cm; Demi-axe horizontal: 0 cm; Demi-axe vertical: 0 cm
IFC_Pset_Géométrie_GRILLE - décalage: 0 cm; Offset latéral: 0 cm; Décalage supérieur: 0 cm; Décalage inférieur: 0 cm; Nombre accrochages latéraux: 0; Nombre d'accrochages supérieurs: 0; Nombre accrochages inférieurs: 0
IFC_Pset_Système de Référence Altimétrique_INFÉRIEUR - NIVEAU: Rez-de-Jardin (Rez-de-Jardin 15545); sous Niveau: <aucun>
IFC_Pset_Données Métré - Surface Vitre 1re Menuiserie: 0 cm2; Surface du Cadre de la 1re Menuiserie: 4900 cm2; Surface 2e Menuiserie: 0 cm2; Surface Vitre 2e Menuiserie: 0 cm2; Surface du Cadre de la 2ème Menuiserie: 0 cm2; Surface du Seuil: 0 cm2; Surface du Seuil intérieur: 0 cm2; Volume du seuil: 0 cm3; Volume du seuil intérieur: 0 cm3; Surface de la Grille: 0 cm2; Volume de la Grille: 0 cm3
IFC_Pset_Matériaux_1° MENUISERIE - Cadre externe: Blanc trafic; Panneau extérieur: Blanc trafic; Poignée: Aluminium satiné
Pset_DoorCommon - Reference: Porte de Secours_1VB[1P plein]_IMP arc (..\Porte classique\1 Vantail Battant\) <aucun>
Name | OverallHeight (cm) | OverallWidth (cm) = Largeur (cm) | __RECOGNIZE__, ID = IFC_Pset_Caractéristiques, ID | Numérotation | Présent | Épaisseur extérieure (cm) = Épaisseur diagonale gauche (cm) = Épaisseur diagonale droite (cm) = Épaisseur diagonale inférieure (cm) = Épaisseur diagonale supérieure (cm) | Décalage (cm) | Côté extérieur | Hauteur (cm) | Rayon Arc (cm) | delta (cm) | Surface 1re Menuiserie (cm2) = Surface de l'Ouverture (cm2) | Surface de l'Ébrasement (cm2)
Porte 76586 | 224.721 | 115.754 | 76586 | 31 | no | 0 | -5 | 1 | 208 | 16.7206 | 4.5 | 25400 | 0
Porte 73786 | 234.68 | 101 | 73786 | 20 | yes | 5 | 0 | 0 | 230 | 4.68011 | 2.51092 | 23400 | 6400 | IFC_Pset_Géométrie_Ébrasement - Données: [a : 50,00; b [gche]: 0,00; b [dte]: 0,00; b [sup]: 0,00; c [gche]: 50,00; c [dte]: 50,00; c [inf]: 50,00; c [sup]: 50,00; d: 0,00] mm

# IfcDoor: Porte de Secours_1VB[1P plein]_IMP arc, Porte 74080
In: Rez-de-Jardin
Type - ParameterTakesPrecedence: no; Sizeable: no; Material: Blanc trafic, Aluminium mat
Type - IfcDoorLiningProperties - LiningDepth: 8 cm; LiningThickness: 3 cm
Description: Porte; OverallHeight: 231.681 cm; OverallWidth: 94.8802 cm
__RECOGNIZE__ - ID: 74080; TPLG: 102; TPLG_OD: 9005; GENERATE: 1
CTLG_EXTERNAL_LINK - 0, DocType: 3; 0, Tag: 100; 0, Crc: -987826624; 1, DocType: 2; 1, Tag: 0; 1, Crc: -746779066; 2, DocType: 2; 2, Tag: 102; 2, Crc: -848491367; 3, DocType: 2; 3, Tag: 105; 3, Crc: -848491367; 4, DocType: 2; 4, Tag: 107; 4, Crc: -1997479717
IFC_PSET_PolygonOffset - polygonOffsetFactor: 2; polygonOffsetUnits: 2
IFC_Pset_Caractéristiques - ID: 74080; Numérotation: 26; Numéro niveau: 02; Titre niveau: Rez-de-Jardin; Modèle 1re menuiserie: Porte de Secours_1VB[1P plein]_IMP arc
IFC_Pset_Géométrie_Ébrasement - Présent: no; Côté supérieur: no; Côté INFÉRIEUR: no; Épaisseur extérieure: 0 cm; Épaisseur latérale gauche: 0 cm; Épaisseur latérale droite: 0 cm; Épiasseur latérale supérieure: 0 cm; Épaisseur diagonale gauche: 0 cm; Épaisseur diagonale droite: 0 cm; Épaisseur diagonale inférieure: 0 cm; Épaisseur diagonale supérieure: 0 cm; Épaisseur intérieur: 0 cm
IFC_Pset_Géométrie_Seuil - Type: Aucun; Épaisseur: 0 cm; Épaisseur interne: 0 cm; Décalage séparation: 0 cm; Appui extérieur: 0 cm; Appui intérieur: 0 cm; Côté latéral externe: 0 cm; Côté latéral interne: 0 cm
IFC_Pset_Géométrie_Chambranle - Position: Aucun; Épaisseur Chambranle intérieur: 0 cm; Longueur Chambranle intérieur: 0 cm; Superposition Chambranle intérieur: 0 cm; Épaisseur Intrados: 0 cm; Épaisseur Chambranle extérieur: 0 cm; Largeur Chambranle extérieur: 0 cm; Superposition Chambranle extérieur: 0 cm; Épaisseur Intrados extérieur: 0 cm
IFC_Pset_Géométrie_CORNICHE depuis profil - Position: Aucune; sets with these values: 2
IFC_Pset_Géométrie_CORNICHE Extérieure à partir d'un profil - Décalage: 0; Angle: 0 deg; Symétrie: no; Fermer: no; sets with these values: 2
IFC_Pset_Géométrie_BASE Extérieure à partir d'un profil - Angle: 0 deg; Symétrie: no; Côté: 0 cm; sets with these values: 2
IFC_Pset_Géométrie_1° MENUISERIE - Position: Intérieur; Décalage: 0 cm
IFC_Pset_Géométrie_2° MENUISERIE - Décalage: 0 cm
IFC_Pset_Géométrie - Côté extérieur: 0; Invertir (dte/gche): yes; Invertir (intérieur/extérieur): yes; Largeur: 94.8802 cm; Hauteur: 221.404 cm; Hauteur 2: 0 cm; Rayon Arc: 10.2764 cm; Rayon Cercle: 0 cm; Demi-axe horizontal: 0 cm; Demi-axe vertical: 0 cm
IFC_Pset_Géométrie_GRILLE - décalage: 0 cm; Offset latéral: 0 cm; Décalage supérieur: 0 cm; Décalage inférieur: 0 cm; Nombre accrochages latéraux: 0; Nombre d'accrochages supérieurs: 0; Nombre accrochages inférieurs: 0
IFC_Pset_Système de Référence Altimétrique_INFÉRIEUR - NIVEAU: Rez-de-Jardin (Rez-de-Jardin 15545); delta: 0 cm; sous Niveau: <aucun>
IFC_Pset_Données Métré - Surface 1re Menuiserie: 21700 cm2; Surface Vitre 1re Menuiserie: 0 cm2; Surface du Cadre de la 1re Menuiserie: 4800 cm2; Surface 2e Menuiserie: 0 cm2; Surface Vitre 2e Menuiserie: 0 cm2; Surface du Cadre de la 2ème Menuiserie: 0 cm2; Surface de l'Ouverture: 21700 cm2; Surface de l'Ébrasement: 0 cm2; Surface du Seuil: 0 cm2; Surface du Seuil intérieur: 0 cm2; Volume du seuil: 0 cm3; Volume du seuil intérieur: 0 cm3; Surface de la Grille: 0 cm2; Volume de la Grille: 0 cm3
IFC_Pset_Matériaux_1° MENUISERIE - Cadre externe: Blanc trafic; Panneau extérieur: Blanc trafic; Poignée: Aluminium mat
Pset_DoorCommon - Reference: Porte de Secours_1VB[1P plein]_IMP arc (..\Porte classique\1 Vantail Battant\) <aucun>

# IfcDoor: Porte de Secours_1VB[1P plein]_IMP arc (2)
In: Rez-de-Jardin
Type - ParameterTakesPrecedence: no; Sizeable: no; Material: Bleu pastel, Aluminium mat
Type - IfcDoorLiningProperties - LiningDepth: 8 cm; LiningThickness: 3 cm
Description: Porte
__RECOGNIZE__ - TPLG: 102; TPLG_OD: 9005; GENERATE: 1
CTLG_EXTERNAL_LINK - 0, DocType: 3; 0, Tag: 100; 0, Crc: -987826624; 1, DocType: 2; 1, Tag: 0; 1, Crc: -746779066; 2, DocType: 2; 2, Tag: 102; 2, Crc: -654192498; 3, DocType: 2; 3, Tag: 105; 3, Crc: -654192498; 4, DocType: 2; 4, Tag: 107; 4, Crc: 913068333
IFC_PSET_PolygonOffset - polygonOffsetFactor: 2; polygonOffsetUnits: 2
IFC_Pset_Caractéristiques - Numéro niveau: 02; Titre niveau: Rez-de-Jardin; Modèle 1re menuiserie: Porte de Secours_1VB[1P plein]_IMP arc
IFC_Pset_Géométrie_Ébrasement - Présent: no; Côté supérieur: no; Côté INFÉRIEUR: no; Épaisseur extérieure: 0 cm; Épaisseur latérale gauche: 0 cm; Épaisseur latérale droite: 0 cm; Épiasseur latérale supérieure: 0 cm; Épaisseur diagonale gauche: 0 cm; Épaisseur diagonale droite: 0 cm; Épaisseur diagonale inférieure: 0 cm; Épaisseur diagonale supérieure: 0 cm; Épaisseur intérieur: 0 cm
IFC_Pset_Géométrie_Seuil - Type: Aucun; Épaisseur: 0 cm; Épaisseur interne: 0 cm; Décalage séparation: 0 cm; Appui extérieur: 0 cm; Appui intérieur: 0 cm; Côté latéral externe: 0 cm; Côté latéral interne: 0 cm
IFC_Pset_Géométrie_Chambranle - Position: Aucun; Épaisseur Chambranle intérieur: 0 cm; Longueur Chambranle intérieur: 0 cm; Superposition Chambranle intérieur: 0 cm; Épaisseur Intrados: 0 cm; Épaisseur Chambranle extérieur: 0 cm; Largeur Chambranle extérieur: 0 cm; Superposition Chambranle extérieur: 0 cm; Épaisseur Intrados extérieur: 0 cm
IFC_Pset_Géométrie_CORNICHE depuis profil - Position: Aucune; sets with these values: 2
IFC_Pset_Géométrie_CORNICHE Extérieure à partir d'un profil - Décalage: 0; Angle: 0 deg; Symétrie: no; Fermer: no; sets with these values: 2
IFC_Pset_Géométrie_BASE Extérieure à partir d'un profil - Angle: 0 deg; Symétrie: no; Côté: 0 cm; sets with these values: 2
IFC_Pset_Géométrie_1° MENUISERIE - Position: Extérieur; Décalage: 0 cm
IFC_Pset_Géométrie_2° MENUISERIE - Décalage: 0 cm
IFC_Pset_Géométrie - Côté extérieur: 0; Invertir (intérieur/extérieur): yes; Hauteur 2: 0 cm; Rayon Cercle: 0 cm; Demi-axe horizontal: 0 cm; Demi-axe vertical: 0 cm
IFC_Pset_Géométrie_GRILLE - décalage: 0 cm; Offset latéral: 0 cm; Décalage supérieur: 0 cm; Décalage inférieur: 0 cm; Nombre accrochages latéraux: 0; Nombre d'accrochages supérieurs: 0; Nombre accrochages inférieurs: 0
IFC_Pset_Système de Référence Altimétrique_INFÉRIEUR - NIVEAU: Rez-de-Jardin (Rez-de-Jardin 15545); delta: 0.601515 cm; sous Niveau: <aucun>
IFC_Pset_Données Métré - Surface Vitre 1re Menuiserie: 0 cm2; Surface 2e Menuiserie: 0 cm2; Surface Vitre 2e Menuiserie: 0 cm2; Surface du Cadre de la 2ème Menuiserie: 0 cm2; Surface de l'Ébrasement: 0 cm2; Surface du Seuil: 0 cm2; Surface du Seuil intérieur: 0 cm2; Volume du seuil: 0 cm3; Volume du seuil intérieur: 0 cm3; Surface de la Grille: 0 cm2; Volume de la Grille: 0 cm3
IFC_Pset_Matériaux_1° MENUISERIE - Cadre externe: Bleu pastel; Panneau extérieur: Bleu pastel; Poignée: Aluminium mat
Pset_DoorCommon - Reference: Porte de Secours_1VB[1P plein]_IMP arc (..\Porte classique\1 Vantail Battant\) <aucun>
Name | OverallHeight (cm) | OverallWidth (cm) = Largeur (cm) | __RECOGNIZE__, ID = IFC_Pset_Caractéristiques, ID | Numérotation | Invertir (dte/gche) | Hauteur (cm) | Rayon Arc (cm) | Surface 1re Menuiserie (cm2) = Surface de l'Ouverture (cm2) | Surface du Cadre de la 1re Menuiserie (cm2)
Porte 78720 | 230.936 | 96.9259 | 78720 | 37 | yes | 219 | 11.9363 | 22000 | 4800
Porte 78747 | 230.507 | 93 | 78747 | 39 | no | 218 | 12.5071 | 21100 | 4700

# IfcDoor: Porte de Secours_1VB[1P plein]_IMP arc, Porte 74102
In: Rez-de-Jardin
Type - ParameterTakesPrecedence: no; Sizeable: no; Material: Jaune pastel, Aluminium satiné, Blanc trafic
Type - IfcDoorLiningProperties - LiningDepth: 8 cm; LiningThickness: 3 cm
Description: Porte; OverallHeight: 228.34 cm; OverallWidth: 96.1394 cm
__RECOGNIZE__ - ID: 74102; TPLG: 102; TPLG_OD: 9005; GENERATE: 1
CTLG_EXTERNAL_LINK - 0, DocType: 3; 0, Tag: 100; 0, Crc: -987826624; 1, DocType: 2; 1, Tag: 0; 1, Crc: -746779066; 2, DocType: 2; 2, Tag: 102; 2, Crc: -848491367; 3, DocType: 2; 3, Tag: 105; 3, Crc: -955079855; 4, DocType: 2; 4, Tag: 107; 4, Crc: 1305662025
IFC_PSET_PolygonOffset - polygonOffsetFactor: 2; polygonOffsetUnits: 2
IFC_Pset_Caractéristiques - ID: 74102; Numérotation: 27; Numéro niveau: 02; Titre niveau: Rez-de-Jardin; Modèle 1re menuiserie: Porte de Secours_1VB[1P plein]_IMP arc
IFC_Pset_Géométrie_Ébrasement - Présent: no; Côté supérieur: no; Côté INFÉRIEUR: no; Épaisseur extérieure: 0 cm; Épaisseur latérale gauche: 0 cm; Épaisseur latérale droite: 0 cm; Épiasseur latérale supérieure: 0 cm; Épaisseur diagonale gauche: 0 cm; Épaisseur diagonale droite: 0 cm; Épaisseur diagonale inférieure: 0 cm; Épaisseur diagonale supérieure: 0 cm; Épaisseur intérieur: 0 cm
IFC_Pset_Géométrie_Seuil - Type: Aucun; Épaisseur: 0 cm; Épaisseur interne: 0 cm; Décalage séparation: 0 cm; Appui extérieur: 0 cm; Appui intérieur: 0 cm; Côté latéral externe: 0 cm; Côté latéral interne: 0 cm
IFC_Pset_Géométrie_Chambranle - Position: Aucun; Épaisseur Chambranle intérieur: 0 cm; Longueur Chambranle intérieur: 0 cm; Superposition Chambranle intérieur: 0 cm; Épaisseur Intrados: 0 cm; Épaisseur Chambranle extérieur: 0 cm; Largeur Chambranle extérieur: 0 cm; Superposition Chambranle extérieur: 0 cm; Épaisseur Intrados extérieur: 0 cm
IFC_Pset_Géométrie_CORNICHE depuis profil - Position: Aucune; sets with these values: 2
IFC_Pset_Géométrie_CORNICHE Extérieure à partir d'un profil - Décalage: 0; Angle: 0 deg; Symétrie: no; Fermer: no; sets with these values: 2
IFC_Pset_Géométrie_BASE Extérieure à partir d'un profil - Angle: 0 deg; Symétrie: no; Côté: 0 cm; sets with these values: 2
IFC_Pset_Géométrie_1° MENUISERIE - Position: Extérieur; Décalage: 0 cm
IFC_Pset_Géométrie_2° MENUISERIE - Décalage: 0 cm
IFC_Pset_Géométrie - Côté extérieur: 0; Invertir (dte/gche): no; Invertir (intérieur/extérieur): yes; Largeur: 96.1394 cm; Hauteur: 218 cm; Hauteur 2: 0 cm; Rayon Arc: 10.3402 cm; Rayon Cercle: 0 cm; Demi-axe horizontal: 0 cm; Demi-axe vertical: 0 cm
IFC_Pset_Géométrie_GRILLE - décalage: 0 cm; Offset latéral: 0 cm; Décalage supérieur: 0 cm; Décalage inférieur: 0 cm; Nombre accrochages latéraux: 0; Nombre d'accrochages supérieurs: 0; Nombre accrochages inférieurs: 0
IFC_Pset_Système de Référence Altimétrique_INFÉRIEUR - NIVEAU: Rez-de-Jardin (Rez-de-Jardin 15545); delta: 1.31165 cm; sous Niveau: <aucun>
IFC_Pset_Données Métré - Surface 1re Menuiserie: 21600 cm2; Surface Vitre 1re Menuiserie: 0 cm2; Surface du Cadre de la 1re Menuiserie: 4700 cm2; Surface 2e Menuiserie: 0 cm2; Surface Vitre 2e Menuiserie: 0 cm2; Surface du Cadre de la 2ème Menuiserie: 0 cm2; Surface de l'Ouverture: 21600 cm2; Surface de l'Ébrasement: 0 cm2; Surface du Seuil: 0 cm2; Surface du Seuil intérieur: 0 cm2; Volume du seuil: 0 cm3; Volume du seuil intérieur: 0 cm3; Surface de la Grille: 0 cm2; Volume de la Grille: 0 cm3
IFC_Pset_Matériaux_1° MENUISERIE - Cadre externe: Blanc trafic; Panneau extérieur: Jaune pastel; Poignée: Aluminium satiné
Pset_DoorCommon - Reference: Porte de Secours_1VB[1P plein]_IMP arc (..\Porte classique\1 Vantail Battant\) <aucun>

# IfcDoor: Porte de Secours_1VB[1P plein]_IMP arc, Porte 73807
In: Rez-de-Jardin
Type - ParameterTakesPrecedence: no; Sizeable: no; Material: Vert clair_porte, Aluminium satiné
Type - IfcDoorLiningProperties - LiningDepth: 8 cm; LiningThickness: 3 cm
Description: Porte; OverallHeight: 224.158 cm; OverallWidth: 82 cm
__RECOGNIZE__ - ID: 73807; TPLG: 102; TPLG_OD: 9005; GENERATE: 1
CTLG_EXTERNAL_LINK - 0, DocType: 3; 0, Tag: 100; 0, Crc: -987826624; 1, DocType: 2; 1, Tag: 0; 1, Crc: -746779066; 2, DocType: 2; 2, Tag: 102; 2, Crc: -1022614176; 3, DocType: 2; 3, Tag: 105; 3, Crc: -1022614176; 4, DocType: 2; 4, Tag: 107; 4, Crc: 1305662025
IFC_PSET_PolygonOffset - polygonOffsetFactor: 2; polygonOffsetUnits: 2
IFC_Pset_Caractéristiques - ID: 73807; Numérotation: 21; Numéro niveau: 02; Titre niveau: Rez-de-Jardin; Modèle 1re menuiserie: Porte de Secours_1VB[1P plein]_IMP arc
IFC_Pset_Géométrie_Ébrasement - Présent: no; Côté supérieur: no; Côté INFÉRIEUR: no; Épaisseur extérieure: 0 cm; Épaisseur latérale gauche: 0 cm; Épaisseur latérale droite: 0 cm; Épiasseur latérale supérieure: 0 cm; Épaisseur diagonale gauche: 0 cm; Épaisseur diagonale droite: 0 cm; Épaisseur diagonale inférieure: 0 cm; Épaisseur diagonale supérieure: 0 cm; Épaisseur intérieur: 0 cm
IFC_Pset_Géométrie_Seuil - Type: Aucun; Épaisseur: 0 cm; Épaisseur interne: 0 cm; Décalage séparation: 0 cm; Appui extérieur: 0 cm; Appui intérieur: 0 cm; Côté latéral externe: 0 cm; Côté latéral interne: 0 cm
IFC_Pset_Géométrie_Chambranle - Position: Aucun; Épaisseur Chambranle intérieur: 0 cm; Longueur Chambranle intérieur: 0 cm; Superposition Chambranle intérieur: 0 cm; Épaisseur Intrados: 0 cm; Épaisseur Chambranle extérieur: 0 cm; Largeur Chambranle extérieur: 0 cm; Superposition Chambranle extérieur: 0 cm; Épaisseur Intrados extérieur: 0 cm
IFC_Pset_Géométrie_CORNICHE depuis profil - Position: Aucune; sets with these values: 2
IFC_Pset_Géométrie_CORNICHE Extérieure à partir d'un profil - Décalage: 0; Angle: 0 deg; Symétrie: no; Fermer: no; sets with these values: 2
IFC_Pset_Géométrie_BASE Extérieure à partir d'un profil - Angle: 0 deg; Symétrie: no; Côté: 0 cm; sets with these values: 2
IFC_Pset_Géométrie_1° MENUISERIE - Position: Extérieur; Décalage: 0 cm
IFC_Pset_Géométrie_2° MENUISERIE - Décalage: 0 cm
IFC_Pset_Géométrie - Côté extérieur: 0; Invertir (dte/gche): no; Invertir (intérieur/extérieur): yes; Largeur: 82 cm; Hauteur: 215 cm; Hauteur 2: 0 cm; Rayon Arc: 9.15792 cm; Rayon Cercle: 0 cm; Demi-axe horizontal: 0 cm; Demi-axe vertical: 0 cm
IFC_Pset_Géométrie_GRILLE - décalage: 0 cm; Offset latéral: 0 cm; Décalage supérieur: 0 cm; Décalage inférieur: 0 cm; Nombre accrochages latéraux: 0; Nombre d'accrochages supérieurs: 0; Nombre accrochages inférieurs: 0
IFC_Pset_Système de Référence Altimétrique_INFÉRIEUR - NIVEAU: Rez-de-Jardin (Rez-de-Jardin 15545); delta: 2.51092 cm; sous Niveau: <aucun>
IFC_Pset_Données Métré - Surface 1re Menuiserie: 18100 cm2; Surface Vitre 1re Menuiserie: 0 cm2; Surface du Cadre de la 1re Menuiserie: 4500 cm2; Surface 2e Menuiserie: 0 cm2; Surface Vitre 2e Menuiserie: 0 cm2; Surface du Cadre de la 2ème Menuiserie: 0 cm2; Surface de l'Ouverture: 18100 cm2; Surface de l'Ébrasement: 0 cm2; Surface du Seuil: 0 cm2; Surface du Seuil intérieur: 0 cm2; Volume du seuil: 0 cm3; Volume du seuil intérieur: 0 cm3; Surface de la Grille: 0 cm2; Volume de la Grille: 0 cm3
IFC_Pset_Matériaux_1° MENUISERIE - Cadre externe: Vert clair_porte; Panneau extérieur: Vert clair_porte; Poignée: Aluminium satiné
Pset_DoorCommon - Reference: Porte de Secours_1VB[1P plein]_IMP arc (..\Porte classique\1 Vantail Battant\) <aucun>

# IfcDoor: Porte de Secours_1VB[1P plein]_IMP arc, Porte 78422
In: Rez-de-Jardin
Type - ParameterTakesPrecedence: no; Sizeable: no; Material: Vert clair_porte, Rouge brillant
Type - IfcDoorLiningProperties - LiningDepth: 8 cm; LiningThickness: 3 cm
Description: Porte; OverallHeight: 228.961 cm; OverallWidth: 82 cm
__RECOGNIZE__ - ID: 78422; TPLG: 102; TPLG_OD: 9005; GENERATE: 1
CTLG_EXTERNAL_LINK - 0, DocType: 3; 0, Tag: 100; 0, Crc: -987826624; 1, DocType: 2; 1, Tag: 0; 1, Crc: -746779066; 2, DocType: 2; 2, Tag: 102; 2, Crc: -1022614176; 3, DocType: 2; 3, Tag: 105; 3, Crc: -1022614176; 4, DocType: 2; 4, Tag: 107; 4, Crc: 1680698050
IFC_PSET_PolygonOffset - polygonOffsetFactor: 2; polygonOffsetUnits: 2
IFC_Pset_Caractéristiques - ID: 78422; Numérotation: 34; Numéro niveau: 02; Titre niveau: Rez-de-Jardin; Modèle 1re menuiserie: Porte de Secours_1VB[1P plein]_IMP arc
IFC_Pset_Géométrie_Ébrasement - Présent: no; Côté supérieur: no; Côté INFÉRIEUR: no; Épaisseur extérieure: 0 cm; Épaisseur latérale gauche: 0 cm; Épaisseur latérale droite: 0 cm; Épiasseur latérale supérieure: 0 cm; Épaisseur diagonale gauche: 0 cm; Épaisseur diagonale droite: 0 cm; Épaisseur diagonale inférieure: 0 cm; Épaisseur diagonale supérieure: 0 cm; Épaisseur intérieur: 0 cm
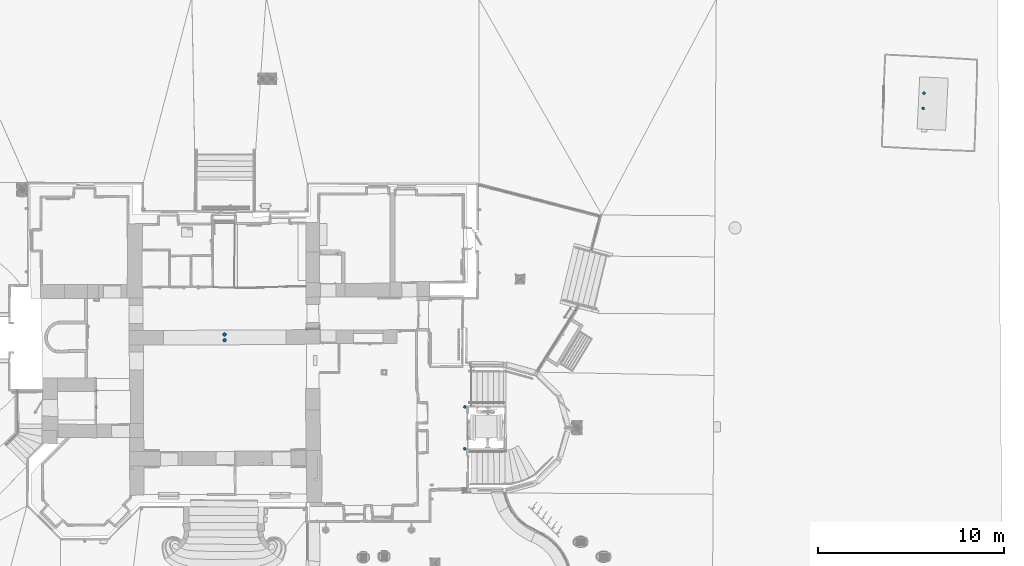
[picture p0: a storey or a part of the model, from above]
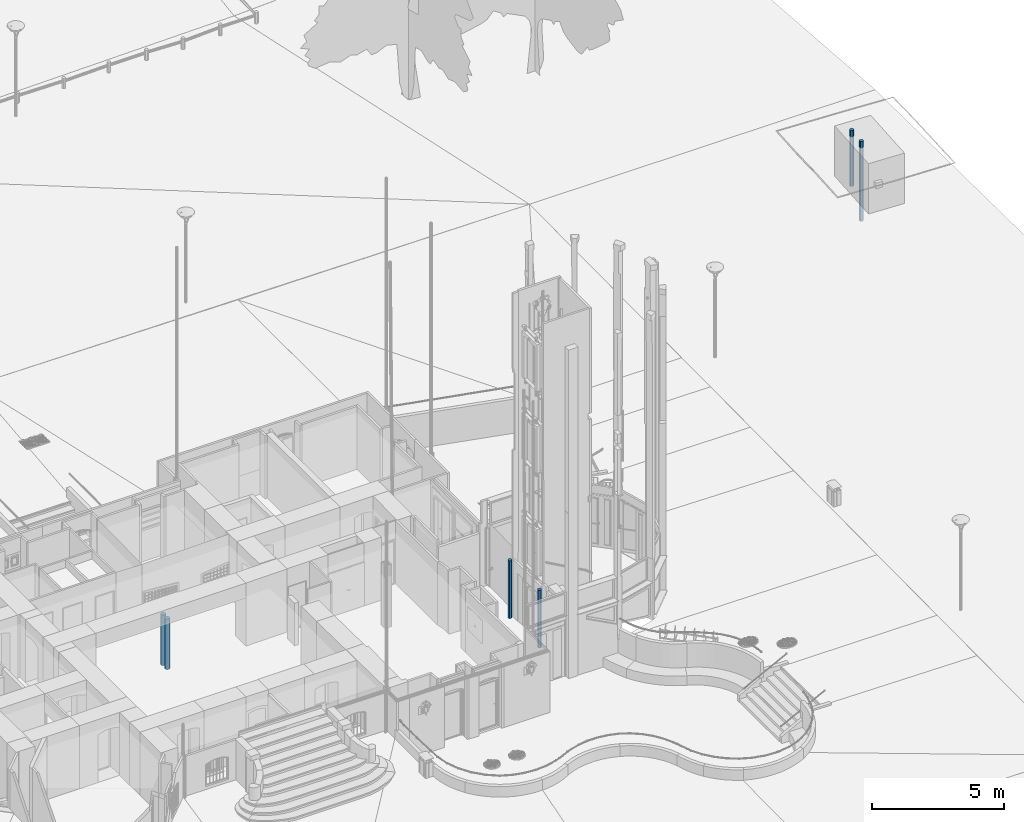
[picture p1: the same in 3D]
Properties of the parts of a building model (IFC2X3), part 6 of 37

# IfcDoor: Porte de Secours_1VB[1P plein]_IMP arc, Porte 78422
IFC_Pset_Géométrie_Seuil - Type: Aucun; Épaisseur: 0 cm; Épaisseur interne: 0 cm; Décalage séparation: 0 cm; Appui extérieur: 0 cm; Appui intérieur: 0 cm; Côté latéral externe: 0 cm; Côté latéral interne: 0 cm
IFC_Pset_Géométrie_Chambranle - Position: Aucun; Épaisseur Chambranle intérieur: 0 cm; Longueur Chambranle intérieur: 0 cm; Superposition Chambranle intérieur: 0 cm; Épaisseur Intrados: 0 cm; Épaisseur Chambranle extérieur: 0 cm; Largeur Chambranle extérieur: 0 cm; Superposition Chambranle extérieur: 0 cm; Épaisseur Intrados extérieur: 0 cm
IFC_Pset_Géométrie_CORNICHE depuis profil - Position: Aucune; sets with these values: 2
IFC_Pset_Géométrie_CORNICHE Extérieure à partir d'un profil - Décalage: 0; Angle: 0 deg; Symétrie: no; Fermer: no; sets with these values: 2
IFC_Pset_Géométrie_BASE Extérieure à partir d'un profil - Angle: 0 deg; Symétrie: no; Côté: 0 cm; sets with these values: 2
IFC_Pset_Géométrie_1° MENUISERIE - Position: Extérieur; Décalage: 0 cm
IFC_Pset_Géométrie_2° MENUISERIE - Décalage: 0 cm
IFC_Pset_Géométrie - Côté extérieur: 0; Invertir (dte/gche): no; Invertir (intérieur/extérieur): yes; Largeur: 82 cm; Hauteur: 219 cm; Hauteur 2: 0 cm; Rayon Arc: 9.9612 cm; Rayon Cercle: 0 cm; Demi-axe horizontal: 0 cm; Demi-axe vertical: 0 cm
IFC_Pset_Géométrie_GRILLE - décalage: 0 cm; Offset latéral: 0 cm; Décalage supérieur: 0 cm; Décalage inférieur: 0 cm; Nombre accrochages latéraux: 0; Nombre d'accrochages supérieurs: 0; Nombre accrochages inférieurs: 0
IFC_Pset_Système de Référence Altimétrique_INFÉRIEUR - NIVEAU: Rez-de-Jardin (Rez-de-Jardin 15545); delta: 0.601515 cm; sous Niveau: <aucun>
IFC_Pset_Données Métré - Surface 1re Menuiserie: 18500 cm2; Surface Vitre 1re Menuiserie: 0 cm2; Surface du Cadre de la 1re Menuiserie: 4500 cm2; Surface 2e Menuiserie: 0 cm2; Surface Vitre 2e Menuiserie: 0 cm2; Surface du Cadre de la 2ème Menuiserie: 0 cm2; Surface de l'Ouverture: 18500 cm2; Surface de l'Ébrasement: 0 cm2; Surface du Seuil: 0 cm2; Surface du Seuil intérieur: 0 cm2; Volume du seuil: 0 cm3; Volume du seuil intérieur: 0 cm3; Surface de la Grille: 0 cm2; Volume de la Grille: 0 cm3
IFC_Pset_Matériaux_1° MENUISERIE - Cadre externe: Vert clair_porte; Panneau extérieur: Vert clair_porte; Poignée: Rouge brillant
Pset_DoorCommon - Reference: Porte de Secours_1VB[1P plein]_IMP arc (..\Porte classique\1 Vantail Battant\) <aucun>

# IfcDoor: Porte de Secours_1VB[1P], Porte 23828
In: Rez-de-chaussée
Type - OperationType: SINGLE_SWING_RIGHT; ParameterTakesPrecedence: yes; Sizeable: no; Material: Aluminium satiné, Blanc trafic
Type - IfcDoorLiningProperties - LiningDepth: 8 cm; LiningThickness: 3 cm
Type - IfcDoorPanelProperties - PanelDepth: 4 cm; PanelOperation: SWINGING; PanelWidth: 1; PanelPosition: RIGHT
Description: Porte; OverallHeight: 207 cm; OverallWidth: 93.4554 cm
__RECOGNIZE__ - ID: 23828; TPLG: 102; TPLG_OD: 9005; GENERATE: 1
CTLG_EXTERNAL_LINK - 0, DocType: 3; 0, Tag: 100; 0, Crc: 159299185; 1, DocType: 2; 1, Tag: 0; 1, Crc: -746779066; 2, DocType: 2; 2, Tag: 102; 2, Crc: -848491367; 3, DocType: 2; 3, Tag: 105; 3, Crc: -848491367; 4, DocType: 2; 4, Tag: 107; 4, Crc: 1305662025
IFC_PSET_PolygonOffset - polygonOffsetFactor: 2; polygonOffsetUnits: 2
IFC_Pset_Caractéristiques - ID: 23828; Numérotation: 03; Numéro niveau: 03; Titre niveau: Rez-de-chaussée; Modèle 1re menuiserie: Porte de Secours_1VB[1P]
IFC_Pset_Géométrie_Ébrasement - Présent: no; Côté supérieur: no; Côté INFÉRIEUR: no; Épaisseur extérieure: 0 cm; Épaisseur latérale gauche: 0 cm; Épaisseur latérale droite: 0 cm; Épiasseur latérale supérieure: 0 cm; Épaisseur diagonale gauche: 0 cm; Épaisseur diagonale droite: 0 cm; Épaisseur diagonale inférieure: 0 cm; Épaisseur diagonale supérieure: 0 cm; Épaisseur intérieur: 0 cm
IFC_Pset_Géométrie_Seuil - Type: Aucun; Épaisseur: 0 cm; Épaisseur interne: 0 cm; Décalage séparation: 0 cm; Appui extérieur: 0 cm; Appui intérieur: 0 cm; Côté latéral externe: 0 cm; Côté latéral interne: 0 cm
IFC_Pset_Géométrie_Chambranle - Position: Aucun; Épaisseur Chambranle intérieur: 0 cm; Longueur Chambranle intérieur: 0 cm; Superposition Chambranle intérieur: 0 cm; Épaisseur Intrados: 0 cm; Épaisseur Chambranle extérieur: 0 cm; Largeur Chambranle extérieur: 0 cm; Superposition Chambranle extérieur: 0 cm; Épaisseur Intrados extérieur: 0 cm
IFC_Pset_Géométrie_CORNICHE depuis profil - Position: Aucune; sets with these values: 2
IFC_Pset_Géométrie_CORNICHE Extérieure à partir d'un profil - Décalage: 0; Angle: 0 deg; Symétrie: no; Fermer: no; sets with these values: 2
IFC_Pset_Géométrie_BASE Extérieure à partir d'un profil - Angle: 0 deg; Symétrie: no; Côté: 0 cm; sets with these values: 2
IFC_Pset_Géométrie_1° MENUISERIE - Position: Centre; Décalage: 0 cm
IFC_Pset_Géométrie_2° MENUISERIE - Décalage: 0 cm
IFC_Pset_Géométrie - Côté extérieur: 1; Invertir (dte/gche): no; Invertir (intérieur/extérieur): yes; Largeur: 93.4554 cm; Hauteur: 207 cm; Hauteur 2: 0 cm; Rayon Arc: 0 cm; Rayon Cercle: 0 cm; Demi-axe horizontal: 0 cm; Demi-axe vertical: 0 cm
IFC_Pset_Géométrie_GRILLE - décalage: 0 cm; Offset latéral: 0 cm; Décalage supérieur: 0 cm; Décalage inférieur: 0 cm; Nombre accrochages latéraux: 0; Nombre d'accrochages supérieurs: 0; Nombre accrochages inférieurs: 0
IFC_Pset_Système de Référence Altimétrique_INFÉRIEUR - NIVEAU: Rez-de-chaussée (Rez-de-chaussée 1047); delta: 0.0128504 cm; sous Niveau: <aucun>
IFC_Pset_Données Métré - Surface 1re Menuiserie: 19300 cm2; Surface Vitre 1re Menuiserie: 0 cm2; Surface du Cadre de la 1re Menuiserie: 1500 cm2; Surface 2e Menuiserie: 0 cm2; Surface Vitre 2e Menuiserie: 0 cm2; Surface du Cadre de la 2ème Menuiserie: 0 cm2; Surface de l'Ouverture: 19300 cm2; Surface de l'Ébrasement: 0 cm2; Surface du Seuil: 0 cm2; Surface du Seuil intérieur: 0 cm2; Volume du seuil: 0 cm3; Volume du seuil intérieur: 0 cm3; Surface de la Grille: 0 cm2; Volume de la Grille: 0 cm3
IFC_Pset_Matériaux_1° MENUISERIE - Cadre externe: Blanc trafic; Panneau extérieur: Blanc trafic; Poignée: Aluminium satiné
Pset_DoorCommon - Reference: Porte de Secours_1VB[1P] (..\Secours\) <aucun>

# IfcDoor: Porte de Secours_blanc_ 2VB verre_tierce+1IMP verre (3)
In: Rez-de-Jardin
Type - OperationType: DOUBLE_DOOR_SINGLE_SWING; ParameterTakesPrecedence: yes; Sizeable: no; Material: Transparent, Béton (01), Blanc trafic, Aluminium mat
Type - IfcDoorLiningProperties - LiningDepth: 8 cm; LiningThickness: 3 cm; ThresholdDepth: 27.5 cm; ThresholdThickness: 3 cm; TransomThickness: 4 cm; TransomOffset: 239.274 cm
Type - IfcDoorPanelProperties - PanelDepth: 4 cm; PanelOperation: SWINGING; PanelWidth: 0.35; PanelPosition: LEFT
Description: Porte; OverallHeight: 282.9 cm
__RECOGNIZE__ - TPLG: 102; TPLG_OD: 9005; GENERATE: 1
CTLG_EXTERNAL_LINK - 0, DocType: 3; 0, Tag: 100; 0, Crc: 1258705165; 1, DocType: 2; 1, Tag: 0; 1, Crc: -746779066; 2, DocType: 2; 2, Tag: 15; 2, Crc: -1434640612; 3, DocType: 2; 3, Tag: 102; 3, Crc: -848491367; 4, DocType: 2; 4, Tag: 104; 4, Crc: -623492449; 5, DocType: 2; 5, Tag: 105; 5, Crc: -848491367; 6, DocType: 2; 6, Tag: 107; 6, Crc: -1997479717
IFC_PSET_PolygonOffset - polygonOffsetFactor: 2; polygonOffsetUnits: 2
IFC_Pset_Caractéristiques - Numéro niveau: 02; Titre niveau: Rez-de-Jardin; Modèle 1re menuiserie: Porte de Secours_blanc_ 2VB verre_tierce+1IMP verre
IFC_Pset_Géométrie_Ébrasement - Présent: no; Côté supérieur: no; Côté INFÉRIEUR: no; Épaisseur extérieure: 0 cm; Épaisseur latérale gauche: 0 cm; Épaisseur latérale droite: 0 cm; Épiasseur latérale supérieure: 0 cm; Épaisseur diagonale gauche: 0 cm; Épaisseur diagonale droite: 0 cm; Épaisseur diagonale inférieure: 0 cm; Épaisseur diagonale supérieure: 0 cm; Épaisseur intérieur: 0 cm
IFC_Pset_Géométrie_Seuil - Type: Unique; Épaisseur: 3 cm; Épaisseur interne: 3 cm; Décalage séparation: 0 cm; Appui extérieur: 21 cm; Appui intérieur: 0 cm; Côté latéral externe: 0 cm; Côté latéral interne: 5 cm
IFC_Pset_Géométrie_Chambranle - Position: Aucun; Épaisseur Chambranle intérieur: 0 cm; Longueur Chambranle intérieur: 0 cm; Superposition Chambranle intérieur: 0 cm; Épaisseur Intrados: 0 cm; Épaisseur Chambranle extérieur: 0 cm; Largeur Chambranle extérieur: 0 cm; Superposition Chambranle extérieur: 0 cm; Épaisseur Intrados extérieur: 0 cm
IFC_Pset_Géométrie_CORNICHE depuis profil - Position: Aucune; sets with these values: 2
IFC_Pset_Géométrie_CORNICHE Extérieure à partir d'un profil - Décalage: 0; Angle: 0 deg; Symétrie: no; Fermer: no; sets with these values: 2
IFC_Pset_Géométrie_BASE Extérieure à partir d'un profil - Angle: 0 deg; Symétrie: no; Côté: 0 cm; sets with these values: 2
IFC_Pset_Géométrie_1° MENUISERIE - Position: Intérieur; Décalage: 0 cm
IFC_Pset_Géométrie_2° MENUISERIE - Décalage: 0 cm
IFC_Pset_Géométrie - Côté extérieur: 1; Invertir (dte/gche): no; Invertir (intérieur/extérieur): no; Hauteur: 282.9 cm; Hauteur 2: 0 cm; Rayon Arc: 0 cm; Rayon Cercle: 0 cm; Demi-axe horizontal: 0 cm; Demi-axe vertical: 0 cm
IFC_Pset_Géométrie_GRILLE - décalage: 0 cm; Offset latéral: 0 cm; Décalage supérieur: 0 cm; Décalage inférieur: 0 cm; Nombre accrochages latéraux: 0; Nombre d'accrochages supérieurs: 0; Nombre accrochages inférieurs: 0
IFC_Pset_Système de Référence Altimétrique_INFÉRIEUR - NIVEAU: Rez-de-Jardin (Rez-de-Jardin 15545); delta: 108.5 cm; sous Niveau: <aucun>
IFC_Pset_Données Métré - Surface 2e Menuiserie: 0 cm2; Surface Vitre 2e Menuiserie: 0 cm2; Surface du Cadre de la 2ème Menuiserie: 0 cm2; Surface de l'Ébrasement: 0 cm2; Surface du Seuil intérieur: 0 cm2; Volume du seuil: 10000 cm3; Volume du seuil intérieur: 10000 cm3; Surface de la Grille: 0 cm2; Volume de la Grille: 0 cm3
IFC_Pset_Matériaux - Seuil: Béton (01)
IFC_Pset_Matériaux_1° MENUISERIE - Cadre externe: Blanc trafic; Verre: Transparent; Panneau extérieur: Blanc trafic; Poignée: Aluminium mat
Pset_DoorCommon - Reference: Porte de Secours_blanc_ 2VB verre_tierce+1IMP verre (..\Secours\) <aucun>
Name | OverallWidth (cm) = Largeur (cm) | __RECOGNIZE__, ID = IFC_Pset_Caractéristiques, ID | Numérotation | Surface 1re Menuiserie (cm2) = Surface de l'Ouverture (cm2) | Surface Vitre 1re Menuiserie (cm2) | Surface du Cadre de la 1re Menuiserie (cm2) | Surface du Seuil (cm2)
Porte 526328 | 141.727 | 526328 | 89 | 40100 | 20900 | 19200 | 3900
Porte 518252 | 142.076 | 518252 | 87 | 40200 | 21000 | 19200 | 3900
Porte 525457 | 145.979 | 525457 | 88 | 41300 | 21900 | 19400 | 4000

# IfcDoor: Porte de Secours_blanc_ 2VB verre_tierce+1IMP vitrée- RDC, Porte 1705930
In: Rez-de-chaussée
Type - OperationType: DOUBLE_DOOR_SINGLE_SWING; ParameterTakesPrecedence: yes; Sizeable: no; Material: Blanc trafic, Aluminium mat
Type - IfcDoorLiningProperties - LiningDepth: 8 cm; LiningThickness: 3 cm; TransomThickness: 4 cm; TransomOffset: 238.161 cm
Type - IfcDoorPanelProperties - PanelDepth: 4 cm; PanelOperation: SWINGING; PanelWidth: 0.35; PanelPosition: LEFT
Description: Porte; OverallHeight: 281.606 cm; OverallWidth: 150.926 cm
__RECOGNIZE__ - ID: 1705930; TPLG: 102; TPLG_OD: 9005; GENERATE: 1
CTLG_EXTERNAL_LINK - 0, DocType: 3; 0, Tag: 100; 0, Crc: -1875548895; 1, DocType: 2; 1, Tag: 0; 1, Crc: -746779066; 2, DocType: 2; 2, Tag: 102; 2, Crc: -848491367; 3, DocType: 2; 3, Tag: 105; 3, Crc: -848491367; 4, DocType: 2; 4, Tag: 107; 4, Crc: 913068333
IFC_PSET_PolygonOffset - polygonOffsetFactor: 2; polygonOffsetUnits: 2
IFC_Pset_Caractéristiques - ID: 1705930; Numérotation: 95; Numéro niveau: 03; Titre niveau: Rez-de-chaussée; Modèle 1re menuiserie: Porte de Secours_blanc_ 2VB verre_tierce+1IMP vitrée- RDC
IFC_Pset_Géométrie_Ébrasement - Présent: no; Côté supérieur: no; Côté INFÉRIEUR: no; Épaisseur extérieure: 0 cm; Épaisseur latérale gauche: 0 cm; Épaisseur latérale droite: 0 cm; Épiasseur latérale supérieure: 0 cm; Épaisseur diagonale gauche: 0 cm; Épaisseur diagonale droite: 0 cm; Épaisseur diagonale inférieure: 0 cm; Épaisseur diagonale supérieure: 0 cm; Épaisseur intérieur: 0 cm
IFC_Pset_Géométrie_Seuil - Type: Aucun; Épaisseur: 0 cm; Épaisseur interne: 0 cm; Décalage séparation: 0 cm; Appui extérieur: 0 cm; Appui intérieur: 0 cm; Côté latéral externe: 0 cm; Côté latéral interne: 0 cm
IFC_Pset_Géométrie_Chambranle - Position: Aucun; Épaisseur Chambranle intérieur: 0 cm; Longueur Chambranle intérieur: 0 cm; Superposition Chambranle intérieur: 0 cm; Épaisseur Intrados: 0 cm; Épaisseur Chambranle extérieur: 0 cm; Largeur Chambranle extérieur: 0 cm; Superposition Chambranle extérieur: 0 cm; Épaisseur Intrados extérieur: 0 cm
IFC_Pset_Géométrie_CORNICHE depuis profil - Position: Aucune; sets with these values: 2
IFC_Pset_Géométrie_CORNICHE Extérieure à partir d'un profil - Décalage: 0; Angle: 0 deg; Symétrie: no; Fermer: no; sets with these values: 2
IFC_Pset_Géométrie_BASE Extérieure à partir d'un profil - Angle: 0 deg; Symétrie: no; Côté: 0 cm; sets with these values: 2
IFC_Pset_Géométrie_1° MENUISERIE - Position: Intérieur; Décalage: 0 cm
IFC_Pset_Géométrie_2° MENUISERIE - Décalage: 0 cm
IFC_Pset_Géométrie - Côté extérieur: 0; Invertir (dte/gche): yes; Invertir (intérieur/extérieur): no; Largeur: 150.926 cm; Hauteur: 281.606 cm; Hauteur 2: 0 cm; Rayon Arc: 0 cm; Rayon Cercle: 0 cm; Demi-axe horizontal: 0 cm; Demi-axe vertical: 0 cm
IFC_Pset_Géométrie_GRILLE - décalage: 0 cm; Offset latéral: 0 cm; Décalage supérieur: 0 cm; Décalage inférieur: 0 cm; Nombre accrochages latéraux: 0; Nombre d'accrochages supérieurs: 0; Nombre accrochages inférieurs: 0
IFC_Pset_Système de Référence Altimétrique_INFÉRIEUR - NIVEAU: Rez-de-chaussée (Rez-de-chaussée 1047); delta: -103.703 cm; sous Niveau: <aucun>
IFC_Pset_Données Métré - Surface 1re Menuiserie: 42500 cm2; Surface Vitre 1re Menuiserie: 0 cm2; Surface du Cadre de la 1re Menuiserie: 19500 cm2; Surface 2e Menuiserie: 0 cm2; Surface Vitre 2e Menuiserie: 0 cm2; Surface du Cadre de la 2ème Menuiserie: 0 cm2; Surface de l'Ouverture: 42500 cm2; Surface de l'Ébrasement: 0 cm2; Surface du Seuil: 0 cm2; Surface du Seuil intérieur: 0 cm2; Volume du seuil: 0 cm3; Volume du seuil intérieur: 0 cm3; Surface de la Grille: 0 cm2; Volume de la Grille: 0 cm3
IFC_Pset_Matériaux_1° MENUISERIE - Cadre externe: Blanc trafic; Panneau extérieur: Blanc trafic; Poignée: Aluminium mat
Pset_DoorCommon - Reference: Porte de Secours_blanc_ 2VB verre_tierce+1IMP vitrée- RDC (..\Secours\) <aucun>

# IfcDoor: Porte_1VB[1P], Porte 77972
In: Rez-de-Jardin
Type - OperationType: SINGLE_SWING_RIGHT; ParameterTakesPrecedence: yes; Sizeable: no; Material: Aluminium satiné, Ivoire clair
Type - IfcDoorLiningProperties - LiningDepth: 8 cm; LiningThickness: 3 cm
Type - IfcDoorPanelProperties - PanelDepth: 6 cm; PanelOperation: SWINGING; PanelWidth: 1; PanelPosition: RIGHT
Description: Porte; OverallHeight: 206 cm; OverallWidth: 84 cm
__RECOGNIZE__ - ID: 77972; TPLG: 102; TPLG_OD: 9005; GENERATE: 1
CTLG_EXTERNAL_LINK - 0, DocType: 3; 0, Tag: 100; 0, Crc: -1099552363; 1, DocType: 2; 1, Tag: 0; 1, Crc: -746779066; 2, DocType: 2; 2, Tag: 102; 2, Crc: 1977773087; 3, DocType: 2; 3, Tag: 105; 3, Crc: 1977773087; 4, DocType: 2; 4, Tag: 107; 4, Crc: -212966465
IFC_PSET_PolygonOffset - polygonOffsetFactor: 2; polygonOffsetUnits: 2
IFC_Pset_Caractéristiques - ID: 77972; Numérotation: 32; Numéro niveau: 02; Titre niveau: Rez-de-Jardin; Modèle 1re menuiserie: Porte_1VB[1P]
IFC_Pset_Géométrie_Ébrasement - Présent: no; Côté supérieur: no; Côté INFÉRIEUR: no; Épaisseur extérieure: 0 cm; Épaisseur latérale gauche: 0 cm; Épaisseur latérale droite: 0 cm; Épiasseur latérale supérieure: 0 cm; Épaisseur diagonale gauche: 0 cm; Épaisseur diagonale droite: 0 cm; Épaisseur diagonale inférieure: 0 cm; Épaisseur diagonale supérieure: 0 cm; Épaisseur intérieur: 0 cm
IFC_Pset_Géométrie_Seuil - Type: Aucun; Épaisseur: 0 cm; Épaisseur interne: 0 cm; Décalage séparation: 0 cm; Appui extérieur: 0 cm; Appui intérieur: 0 cm; Côté latéral externe: 0 cm; Côté latéral interne: 0 cm
IFC_Pset_Géométrie_Chambranle - Position: Aucun; Épaisseur Chambranle intérieur: 0 cm; Longueur Chambranle intérieur: 0 cm; Superposition Chambranle intérieur: 0 cm; Épaisseur Intrados: 0 cm; Épaisseur Chambranle extérieur: 0 cm; Largeur Chambranle extérieur: 0 cm; Superposition Chambranle extérieur: 0 cm; Épaisseur Intrados extérieur: 0 cm
IFC_Pset_Géométrie_CORNICHE depuis profil - Position: Aucune; sets with these values: 2
IFC_Pset_Géométrie_CORNICHE Extérieure à partir d'un profil - Décalage: 0; Angle: 0 deg; Symétrie: no; Fermer: no; sets with these values: 2
IFC_Pset_Géométrie_BASE Extérieure à partir d'un profil - Angle: 0 deg; Symétrie: no; Côté: 0 cm; sets with these values: 2
IFC_Pset_Géométrie_1° MENUISERIE - Position: Extérieur; Décalage: 0 cm
IFC_Pset_Géométrie_2° MENUISERIE - Décalage: 0 cm
IFC_Pset_Géométrie - Côté extérieur: 1; Invertir (dte/gche): yes; Invertir (intérieur/extérieur): no; Largeur: 84 cm; Hauteur: 206 cm; Hauteur 2: 0 cm; Rayon Arc: 0 cm; Rayon Cercle: 0 cm; Demi-axe horizontal: 0 cm; Demi-axe vertical: 0 cm
IFC_Pset_Géométrie_GRILLE - décalage: 0 cm; Offset latéral: 0 cm; Décalage supérieur: 0 cm; Décalage inférieur: 0 cm; Nombre accrochages latéraux: 0; Nombre d'accrochages supérieurs: 0; Nombre accrochages inférieurs: 0
IFC_Pset_Système de Référence Altimétrique_INFÉRIEUR - NIVEAU: Rez-de-Jardin (Rez-de-Jardin 15545); delta: 2 cm; sous Niveau: <aucun>
IFC_Pset_Données Métré - Surface 1re Menuiserie: 17300 cm2; Surface Vitre 1re Menuiserie: 0 cm2; Surface du Cadre de la 1re Menuiserie: 3700 cm2; Surface 2e Menuiserie: 0 cm2; Surface Vitre 2e Menuiserie: 0 cm2; Surface du Cadre de la 2ème Menuiserie: 0 cm2; Surface de l'Ouverture: 17300 cm2; Surface de l'Ébrasement: 0 cm2; Surface du Seuil: 0 cm2; Surface du Seuil intérieur: 0 cm2; Volume du seuil: 0 cm3; Volume du seuil intérieur: 0 cm3; Surface de la Grille: 0 cm2; Volume de la Grille: 0 cm3
IFC_Pset_Matériaux_1° MENUISERIE - Cadre externe: Ivoire clair; Panneau extérieur: Ivoire clair; Poignée: Aluminium satiné
Pset_DoorCommon - Reference: Porte_1VB[1P] (..\Porte classique\1 Vantail Battant\) <aucun>

# IfcDoor: Porte_1VB[1P], Porte 132698
In: Niveau 1
Type - OperationType: SINGLE_SWING_RIGHT; ParameterTakesPrecedence: yes; Sizeable: no; Material: Aluminium satiné, Noyer 01
Type - IfcDoorLiningProperties - LiningDepth: 8 cm; LiningThickness: 3 cm
Type - IfcDoorPanelProperties - PanelDepth: 6 cm; PanelOperation: SWINGING; PanelWidth: 1; PanelPosition: RIGHT
Description: Porte; OverallHeight: 210 cm; OverallWidth: 80 cm
__RECOGNIZE__ - ID: 132698; TPLG: 102; TPLG_OD: 9005; GENERATE: 1
CTLG_EXTERNAL_LINK - 0, DocType: 3; 0, Tag: 100; 0, Crc: -1099552363; 1, DocType: 2; 1, Tag: 0; 1, Crc: -746779066; 2, DocType: 2; 2, Tag: 102; 2, Crc: -990824515; 3, DocType: 2; 3, Tag: 105; 3, Crc: -990824515; 4, DocType: 2; 4, Tag: 107; 4, Crc: -212966465
IFC_PSET_PolygonOffset - polygonOffsetFactor: 2; polygonOffsetUnits: 2
IFC_Pset_Caractéristiques - ID: 132698; Numérotation: 65; Numéro niveau: 04; Titre niveau: Niveau 1; Modèle 1re menuiserie: Porte_1VB[1P]
IFC_Pset_Géométrie_Ébrasement - Présent: no; Côté supérieur: no; Côté INFÉRIEUR: no; Épaisseur extérieure: 0 cm; Épaisseur latérale gauche: 0 cm; Épaisseur latérale droite: 0 cm; Épiasseur latérale supérieure: 0 cm; Épaisseur diagonale gauche: 0 cm; Épaisseur diagonale droite: 0 cm; Épaisseur diagonale inférieure: 0 cm; Épaisseur diagonale supérieure: 0 cm; Épaisseur intérieur: 0 cm
IFC_Pset_Géométrie_Seuil - Type: Aucun; Épaisseur: 0 cm; Épaisseur interne: 0 cm; Décalage séparation: 0 cm; Appui extérieur: 0 cm; Appui intérieur: 0 cm; Côté latéral externe: 0 cm; Côté latéral interne: 0 cm
IFC_Pset_Géométrie_Chambranle - Position: Aucun; Épaisseur Chambranle intérieur: 0 cm; Longueur Chambranle intérieur: 0 cm; Superposition Chambranle intérieur: 0 cm; Épaisseur Intrados: 0 cm; Épaisseur Chambranle extérieur: 0 cm; Largeur Chambranle extérieur: 0 cm; Superposition Chambranle extérieur: 0 cm; Épaisseur Intrados extérieur: 0 cm
IFC_Pset_Géométrie_CORNICHE depuis profil - Position: Aucune; sets with these values: 2
IFC_Pset_Géométrie_CORNICHE Extérieure à partir d'un profil - Décalage: 0; Angle: 0 deg; Symétrie: no; Fermer: no; sets with these values: 2
IFC_Pset_Géométrie_BASE Extérieure à partir d'un profil - Angle: 0 deg; Symétrie: no; Côté: 0 cm; sets with these values: 2
IFC_Pset_Géométrie_1° MENUISERIE - Position: Extérieur; Décalage: 0 cm
IFC_Pset_Géométrie_2° MENUISERIE - Décalage: 0 cm
IFC_Pset_Géométrie - Côté extérieur: 1; Invertir (dte/gche): no; Invertir (intérieur/extérieur): yes; Largeur: 80 cm; Hauteur: 210 cm; Hauteur 2: 0 cm; Rayon Arc: 0 cm; Rayon Cercle: 0 cm; Demi-axe horizontal: 0 cm; Demi-axe vertical: 0 cm
IFC_Pset_Géométrie_GRILLE - décalage: 0 cm; Offset latéral: 0 cm; Décalage supérieur: 0 cm; Décalage inférieur: 0 cm; Nombre accrochages latéraux: 0; Nombre d'accrochages supérieurs: 0; Nombre accrochages inférieurs: 0
IFC_Pset_Système de Référence Altimétrique_INFÉRIEUR - NIVEAU: Niveau 1 (Niveau 1 2343); delta: 0.0128504 cm; sous Niveau: <aucun>
IFC_Pset_Données Métré - Surface 1re Menuiserie: 16800 cm2; Surface Vitre 1re Menuiserie: 0 cm2; Surface du Cadre de la 1re Menuiserie: 3700 cm2; Surface 2e Menuiserie: 0 cm2; Surface Vitre 2e Menuiserie: 0 cm2; Surface du Cadre de la 2ème Menuiserie: 0 cm2; Surface de l'Ouverture: 16800 cm2; Surface de l'Ébrasement: 0 cm2; Surface du Seuil: 0 cm2; Surface du Seuil intérieur: 0 cm2; Volume du seuil: 0 cm3; Volume du seuil intérieur: 0 cm3; Surface de la Grille: 0 cm2; Volume de la Grille: 0 cm3
IFC_Pset_Matériaux_1° MENUISERIE - Cadre externe: Noyer 01; Panneau extérieur: Noyer 01; Poignée: Aluminium satiné
Pset_DoorCommon - Reference: Porte_1VB[1P] (..\Porte classique\1 Vantail Battant\) <aucun>

# IfcDoor: Porte_1VB[1P] (4)
In: Niveau 1
Type - OperationType: SINGLE_SWING_RIGHT; ParameterTakesPrecedence: yes; Sizeable: no; Material: Blanc gris, Aluminium satiné
Type - IfcDoorLiningProperties - LiningDepth: 8 cm; LiningThickness: 3 cm
Type - IfcDoorPanelProperties - PanelDepth: 6 cm; PanelOperation: SWINGING; PanelWidth: 1; PanelPosition: RIGHT
Description: Porte; OverallHeight: 208 cm
__RECOGNIZE__ - TPLG: 102; TPLG_OD: 9005; GENERATE: 1
CTLG_EXTERNAL_LINK - 0, DocType: 3; 0, Tag: 100; 0, Crc: -1099552363; 1, DocType: 2; 1, Tag: 0; 1, Crc: -746779066; 2, DocType: 2; 2, Tag: 102; 2, Crc: 2064387956; 3, DocType: 2; 3, Tag: 105; 3, Crc: 2064387956; 4, DocType: 2; 4, Tag: 107; 4, Crc: -212966465
IFC_PSET_PolygonOffset - polygonOffsetFactor: 2; polygonOffsetUnits: 2
IFC_Pset_Caractéristiques - Numéro niveau: 04; Titre niveau: Niveau 1; Modèle 1re menuiserie: Porte_1VB[1P]
IFC_Pset_Géométrie_Ébrasement - Présent: no; Côté supérieur: no; Côté INFÉRIEUR: no; Épaisseur extérieure: 0 cm; Épaisseur latérale gauche: 0 cm; Épaisseur latérale droite: 0 cm; Épiasseur latérale supérieure: 0 cm; Épaisseur diagonale gauche: 0 cm; Épaisseur diagonale droite: 0 cm; Épaisseur diagonale inférieure: 0 cm; Épaisseur diagonale supérieure: 0 cm; Épaisseur intérieur: 0 cm
IFC_Pset_Géométrie_Seuil - Type: Aucun; Épaisseur: 0 cm; Épaisseur interne: 0 cm; Décalage séparation: 0 cm; Appui extérieur: 0 cm; Appui intérieur: 0 cm; Côté latéral externe: 0 cm; Côté latéral interne: 0 cm
IFC_Pset_Géométrie_Chambranle - Position: Aucun; Épaisseur Chambranle intérieur: 0 cm; Longueur Chambranle intérieur: 0 cm; Superposition Chambranle intérieur: 0 cm; Épaisseur Intrados: 0 cm; Épaisseur Chambranle extérieur: 0 cm; Largeur Chambranle extérieur: 0 cm; Superposition Chambranle extérieur: 0 cm; Épaisseur Intrados extérieur: 0 cm
IFC_Pset_Géométrie_CORNICHE depuis profil - Position: Aucune; sets with these values: 2
IFC_Pset_Géométrie_CORNICHE Extérieure à partir d'un profil - Décalage: 0; Angle: 0 deg; Symétrie: no; Fermer: no; sets with these values: 2
IFC_Pset_Géométrie_BASE Extérieure à partir d'un profil - Angle: 0 deg; Symétrie: no; Côté: 0 cm; sets with these values: 2
IFC_Pset_Géométrie_1° MENUISERIE - Position: Extérieur
IFC_Pset_Géométrie_2° MENUISERIE - Décalage: 0 cm
IFC_Pset_Géométrie - Côté extérieur: 1; Hauteur: 208 cm; Hauteur 2: 0 cm; Rayon Arc: 0 cm; Rayon Cercle: 0 cm; Demi-axe horizontal: 0 cm; Demi-axe vertical: 0 cm
IFC_Pset_Géométrie_GRILLE - décalage: 0 cm; Offset latéral: 0 cm; Décalage supérieur: 0 cm; Décalage inférieur: 0 cm; Nombre accrochages latéraux: 0; Nombre d'accrochages supérieurs: 0; Nombre accrochages inférieurs: 0
IFC_Pset_Système de Référence Altimétrique_INFÉRIEUR - NIVEAU: Niveau 1 (Niveau 1 2343); delta: 0.0128504 cm; sous Niveau: <aucun>
IFC_Pset_Données Métré - Surface Vitre 1re Menuiserie: 0 cm2; Surface 2e Menuiserie: 0 cm2; Surface Vitre 2e Menuiserie: 0 cm2; Surface du Cadre de la 2ème Menuiserie: 0 cm2; Surface de l'Ébrasement: 0 cm2; Surface du Seuil: 0 cm2; Surface du Seuil intérieur: 0 cm2; Volume du seuil: 0 cm3; Volume du seuil intérieur: 0 cm3; Surface de la Grille: 0 cm2; Volume de la Grille: 0 cm3
IFC_Pset_Matériaux_1° MENUISERIE - Cadre externe: Blanc gris; Panneau extérieur: Blanc gris; Poignée: Aluminium satiné
Pset_DoorCommon - Reference: Porte_1VB[1P] (..\Porte classique\1 Vantail Battant\) <aucun>
Name | OverallWidth (cm) = Largeur (cm) | __RECOGNIZE__, ID = IFC_Pset_Caractéristiques, ID | Numérotation | Décalage (cm) | Invertir (dte/gche) | Invertir (intérieur/extérieur) | Surface 1re Menuiserie (cm2) = Surface de l'Ouverture (cm2) | Surface du Cadre de la 1re Menuiserie (cm2)
Porte 132689 | 80.7351 | 132689 | 64 | 0 | no | yes | 16800 | 3600
Porte 94968 | 99.8667 | 94968 | 41 | -1.5 | no | no | 20800 | 3900
Porte 103082 | 73 | 103082 | 42 | 0 | no | no | 15200 | 3600
Porte 103085 | 73 | 103085 | 43 | 0 | yes | no | 15200 | 3600

# IfcDoor: Porte_1VB[1P] (10)
Type - OperationType: SINGLE_SWING_RIGHT; ParameterTakesPrecedence: yes; Sizeable: no; Material: Blanc trafic, Aluminium satiné
Type - IfcDoorLiningProperties - LiningDepth: 8 cm; LiningThickness: 3 cm
Type - IfcDoorPanelProperties - PanelDepth: 6 cm; PanelOperation: SWINGING; PanelWidth: 1; PanelPosition: RIGHT
Description: Porte
__RECOGNIZE__ - TPLG: 102; TPLG_OD: 9005; GENERATE: 1
CTLG_EXTERNAL_LINK - 0, DocType: 3; 0, Tag: 100; 0, Crc: -1099552363; 1, DocType: 2; 1, Tag: 0; 1, Crc: -746779066; 2, DocType: 2; 2, Tag: 102; 2, Crc: -848491367; 3, DocType: 2; 3, Tag: 105; 3, Crc: -848491367; 4, DocType: 2; 4, Tag: 107; 4, Crc: -212966465
IFC_PSET_PolygonOffset - polygonOffsetFactor: 2; polygonOffsetUnits: 2
IFC_Pset_Caractéristiques - Modèle 1re menuiserie: Porte_1VB[1P]
IFC_Pset_Géométrie_Ébrasement - Présent: no; Côté supérieur: no; Côté INFÉRIEUR: no; Épaisseur extérieure: 0 cm; Épaisseur latérale gauche: 0 cm; Épaisseur latérale droite: 0 cm; Épiasseur latérale supérieure: 0 cm; Épaisseur diagonale gauche: 0 cm; Épaisseur diagonale droite: 0 cm; Épaisseur diagonale inférieure: 0 cm; Épaisseur diagonale supérieure: 0 cm; Épaisseur intérieur: 0 cm
IFC_Pset_Géométrie_Seuil - Type: Aucun; Épaisseur: 0 cm; Épaisseur interne: 0 cm; Décalage séparation: 0 cm; Appui extérieur: 0 cm; Appui intérieur: 0 cm; Côté latéral externe: 0 cm; Côté latéral interne: 0 cm
IFC_Pset_Géométrie_Chambranle - Position: Aucun; Épaisseur Chambranle intérieur: 0 cm; Longueur Chambranle intérieur: 0 cm; Superposition Chambranle intérieur: 0 cm; Épaisseur Intrados: 0 cm; Épaisseur Chambranle extérieur: 0 cm; Largeur Chambranle extérieur: 0 cm; Superposition Chambranle extérieur: 0 cm; Épaisseur Intrados extérieur: 0 cm
IFC_Pset_Géométrie_CORNICHE depuis profil - Position: Aucune; sets with these values: 2
IFC_Pset_Géométrie_CORNICHE Extérieure à partir d'un profil - Décalage: 0; Angle: 0 deg; Symétrie: no; Fermer: no; sets with these values: 2
IFC_Pset_Géométrie_BASE Extérieure à partir d'un profil - Angle: 0 deg; Symétrie: no; Côté: 0 cm; sets with these values: 2
IFC_Pset_Géométrie_1° MENUISERIE - Décalage: 0 cm
IFC_Pset_Géométrie_2° MENUISERIE - Décalage: 0 cm
IFC_Pset_Géométrie - Hauteur 2: 0 cm; Rayon Arc: 0 cm; Rayon Cercle: 0 cm; Demi-axe horizontal: 0 cm; Demi-axe vertical: 0 cm
IFC_Pset_Géométrie_GRILLE - décalage: 0 cm; Offset latéral: 0 cm; Décalage supérieur: 0 cm; Décalage inférieur: 0 cm; Nombre accrochages latéraux: 0; Nombre d'accrochages supérieurs: 0; Nombre accrochages inférieurs: 0
IFC_Pset_Système de Référence Altimétrique_INFÉRIEUR - sous Niveau: <aucun>
IFC_Pset_Données Métré - Surface Vitre 1re Menuiserie: 0 cm2; Surface 2e Menuiserie: 0 cm2; Surface Vitre 2e Menuiserie: 0 cm2; Surface du Cadre de la 2ème Menuiserie: 0 cm2; Surface de l'Ébrasement: 0 cm2; Surface du Seuil: 0 cm2; Surface du Seuil intérieur: 0 cm2; Volume du seuil: 0 cm3; Volume du seuil intérieur: 0 cm3; Surface de la Grille: 0 cm2; Volume de la Grille: 0 cm3
IFC_Pset_Matériaux_1° MENUISERIE - Cadre externe: Blanc trafic; Panneau extérieur: Blanc trafic; Poignée: Aluminium satiné
Pset_DoorCommon - Reference: Porte_1VB[1P] (..\Porte classique\1 Vantail Battant\) <aucun>
Name | In | OverallHeight (cm) = Hauteur (cm) | OverallWidth (cm) = Largeur (cm) | __RECOGNIZE__, ID = IFC_Pset_Caractéristiques, ID | Numérotation | Numéro niveau | Titre niveau | Position | Côté extérieur | Invertir (dte/gche) | Invertir (intérieur/extérieur) | NIVEAU | delta (cm) | Surface 1re Menuiserie (cm2) = Surface de l'Ouverture (cm2) | Surface du Cadre de la 1re Menuiserie (cm2)
Porte 74106 | Rez-de-Jardin | 208 | 96 | 74106 | 28 | 02 | Rez-de-Jardin | Extérieur | 0 | no | yes | Rez-de-Jardin (Rez-de-Jardin 15545) | 1.31165 | 20000 | 3800
Porte 74108 | Rez-de-Jardin | 208 | 87 | 74108 | 29 | 02 | Rez-de-Jardin | Extérieur | 0 | no | yes | Rez-de-Jardin (Rez-de-Jardin 15545) | 1.31165 | 18100 | 3700
Porte 74110 | Rez-de-Jardin | 210 | 86 | 74110 | 30 | 02 | Rez-de-Jardin | Extérieur | 0 | yes | yes | Rez-de-Jardin (Rez-de-Jardin 15545) | 1.31165 | 18100 | 3700
Porte 111275 | Niveau 1 | 209.883 | 96.8319 | 111275 | 53 | 04 | Niveau 1 | Extérieur | 1 | no | yes | Niveau 1 (Niveau 1 2343) | 0.0128504 | 20300 | 3800
Porte 121337 | Niveau 1 | 203.5 | 85.1039 | 121337 | 61 | 04 | Niveau 1 | Extérieur | 0 | no | no | Niveau 1 (Niveau 1 2343) | 0.0128504 | 17300 | 3600
Porte 118693 | Niveau 1 | 207 | 95 | 118693 | 55 | 04 | Niveau 1 | Centre | 0 | yes | no | Niveau 1 (Niveau 1 2343) | 0.0128504 | 19700 | 3800
Porte 115410 | Niveau 1 | 209.883 | 95.1134 | 115410 | 54 | 04 | Niveau 1 | Extérieur | 1 | yes | yes | Niveau 1 (Niveau 1 2343) | 0.0128504 | 20000 | 3800
Porte 119879 | Niveau 1 | 207.5 | 97 | 119879 | 56 | 04 | Niveau 1 | Centre | 1 | no | yes | Niveau 1 (Niveau 1 2343) | 0.0128504 | 20100 | 3800
Porte 132088 | Niveau 1 | 207 | 85 | 132088 | 62 | 04 | Niveau 1 | Extérieur | 0 | no | no | Niveau 1 (Niveau 1 2343) | 0.0128504 | 17600 | 3700
Porte 132384 | Niveau 1 | 208.5 | 99.7598 | 132384 | 63 | 04 | Niveau 1 | Extérieur | 0 | no | no | Niveau 1 (Niveau 1 2343) | 0.0128504 | 20800 | 3900

# IfcDoor: Porte_1VB[1P] (4)
In: Niveau 1
Type - OperationType: SINGLE_SWING_RIGHT; ParameterTakesPrecedence: yes; Sizeable: no; Material: Bleu france, Aluminium satiné
Type - IfcDoorLiningProperties - LiningDepth: 8 cm; LiningThickness: 3 cm
Type - IfcDoorPanelProperties - PanelDepth: 6 cm; PanelOperation: SWINGING; PanelWidth: 1; PanelPosition: RIGHT
Description: Porte
__RECOGNIZE__ - TPLG: 102; TPLG_OD: 9005; GENERATE: 1
CTLG_EXTERNAL_LINK - 0, DocType: 3; 0, Tag: 100; 0, Crc: -1099552363; 1, DocType: 2; 1, Tag: 0; 1, Crc: -746779066; 2, DocType: 2; 2, Tag: 102; 2, Crc: 1181025438; 3, DocType: 2; 3, Tag: 105; 3, Crc: 1181025438; 4, DocType: 2; 4, Tag: 107; 4, Crc: -212966465
IFC_PSET_PolygonOffset - polygonOffsetFactor: 2; polygonOffsetUnits: 2
IFC_Pset_Caractéristiques - Numéro niveau: 04; Titre niveau: Niveau 1; Modèle 1re menuiserie: Porte_1VB[1P]
IFC_Pset_Géométrie_Ébrasement - Présent: no; Côté supérieur: no; Côté INFÉRIEUR: no; Épaisseur extérieure: 0 cm; Épaisseur latérale gauche: 0 cm; Épaisseur latérale droite: 0 cm; Épiasseur latérale supérieure: 0 cm; Épaisseur diagonale gauche: 0 cm; Épaisseur diagonale droite: 0 cm; Épaisseur diagonale inférieure: 0 cm; Épaisseur diagonale supérieure: 0 cm; Épaisseur intérieur: 0 cm
IFC_Pset_Géométrie_Seuil - Type: Aucun; Épaisseur: 0 cm; Épaisseur interne: 0 cm; Décalage séparation: 0 cm; Appui extérieur: 0 cm; Appui intérieur: 0 cm; Côté latéral externe: 0 cm; Côté latéral interne: 0 cm
IFC_Pset_Géométrie_Chambranle - Position: Aucun; Épaisseur Chambranle intérieur: 0 cm; Longueur Chambranle intérieur: 0 cm; Superposition Chambranle intérieur: 0 cm; Épaisseur Intrados: 0 cm; Épaisseur Chambranle extérieur: 0 cm; Largeur Chambranle extérieur: 0 cm; Superposition Chambranle extérieur: 0 cm; Épaisseur Intrados extérieur: 0 cm
IFC_Pset_Géométrie_CORNICHE depuis profil - Position: Aucune; sets with these values: 2
IFC_Pset_Géométrie_CORNICHE Extérieure à partir d'un profil - Décalage: 0; Angle: 0 deg; Symétrie: no; Fermer: no; sets with these values: 2
IFC_Pset_Géométrie_BASE Extérieure à partir d'un profil - Angle: 0 deg; Symétrie: no; Côté: 0 cm; sets with these values: 2
IFC_Pset_Géométrie_1° MENUISERIE - Position: Extérieur; Décalage: 0 cm
IFC_Pset_Géométrie_2° MENUISERIE - Décalage: 0 cm
IFC_Pset_Géométrie - Hauteur 2: 0 cm; Rayon Arc: 0 cm; Rayon Cercle: 0 cm; Demi-axe horizontal: 0 cm; Demi-axe vertical: 0 cm
IFC_Pset_Géométrie_GRILLE - décalage: 0 cm; Offset latéral: 0 cm; Décalage supérieur: 0 cm; Décalage inférieur: 0 cm; Nombre accrochages latéraux: 0; Nombre d'accrochages supérieurs: 0; Nombre accrochages inférieurs: 0
IFC_Pset_Système de Référence Altimétrique_INFÉRIEUR - NIVEAU: Niveau 1 (Niveau 1 2343); delta: 0.0128504 cm; sous Niveau: <aucun>
IFC_Pset_Données Métré - Surface Vitre 1re Menuiserie: 0 cm2; Surface 2e Menuiserie: 0 cm2; Surface Vitre 2e Menuiserie: 0 cm2; Surface du Cadre de la 2ème Menuiserie: 0 cm2; Surface de l'Ébrasement: 0 cm2; Surface du Seuil: 0 cm2; Surface du Seuil intérieur: 0 cm2; Volume du seuil: 0 cm3; Volume du seuil intérieur: 0 cm3; Surface de la Grille: 0 cm2; Volume de la Grille: 0 cm3
IFC_Pset_Matériaux_1° MENUISERIE - Cadre externe: Bleu france; Panneau extérieur: Bleu france; Poignée: Aluminium satiné
Pset_DoorCommon - Reference: Porte_1VB[1P] (..\Porte classique\1 Vantail Battant\) <aucun>
Name | OverallHeight (cm) = Hauteur (cm) | OverallWidth (cm) = Largeur (cm) | __RECOGNIZE__, ID = IFC_Pset_Caractéristiques, ID | Numérotation | Côté extérieur | Invertir (dte/gche) | Invertir (intérieur/extérieur) | Surface 1re Menuiserie (cm2) = Surface de l'Ouverture (cm2) | Surface du Cadre de la 1re Menuiserie (cm2)
Porte 103562 | 204.4 | 96 | 103562 | 48 | 1 | yes | no | 19600 | 3800
Porte 103170 | 202 | 93 | 103170 | 45 | 0 | no | yes | 18800 | 3700
Porte 103171 | 207 | 73.0411 | 103171 | 46 | 1 | yes | no | 15100 | 3500
Porte 103561 | 201.4 | 68.9959 | 103561 | 47 | 0 | no | yes | 13900 | 3400

# IfcDoor: Porte_1VB[1P], Porte 78717
In: Rez-de-Jardin
Type - OperationType: SINGLE_SWING_RIGHT; ParameterTakesPrecedence: yes; Sizeable: no; Material: Bleu pastel, Aluminium satiné
Type - IfcDoorLiningProperties - LiningDepth: 8 cm; LiningThickness: 3 cm
Type - IfcDoorPanelProperties - PanelDepth: 6 cm; PanelOperation: SWINGING; PanelWidth: 1; PanelPosition: RIGHT
Description: Porte; OverallHeight: 206.001 cm; OverallWidth: 79.0044 cm
__RECOGNIZE__ - ID: 78717; TPLG: 102; TPLG_OD: 9005; GENERATE: 1
CTLG_EXTERNAL_LINK - 0, DocType: 3; 0, Tag: 100; 0, Crc: -1099552363; 1, DocType: 2; 1, Tag: 0; 1, Crc: -746779066; 2, DocType: 2; 2, Tag: 102; 2, Crc: -654192498; 3, DocType: 2; 3, Tag: 105; 3, Crc: -654192498; 4, DocType: 2; 4, Tag: 107; 4, Crc: -212966465
IFC_PSET_PolygonOffset - polygonOffsetFactor: 2; polygonOffsetUnits: 2
IFC_Pset_Caractéristiques - ID: 78717; Numérotation: 36; Numéro niveau: 02; Titre niveau: Rez-de-Jardin; Modèle 1re menuiserie: Porte_1VB[1P]
IFC_Pset_Géométrie_Ébrasement - Présent: no; Côté supérieur: no; Côté INFÉRIEUR: no; Épaisseur extérieure: 0 cm; Épaisseur latérale gauche: 0 cm; Épaisseur latérale droite: 0 cm; Épiasseur latérale supérieure: 0 cm; Épaisseur diagonale gauche: 0 cm; Épaisseur diagonale droite: 0 cm; Épaisseur diagonale inférieure: 0 cm; Épaisseur diagonale supérieure: 0 cm; Épaisseur intérieur: 0 cm
IFC_Pset_Géométrie_Seuil - Type: Aucun; Épaisseur: 0 cm; Épaisseur interne: 0 cm; Décalage séparation: 0 cm; Appui extérieur: 0 cm; Appui intérieur: 0 cm; Côté latéral externe: 0 cm; Côté latéral interne: 0 cm
IFC_Pset_Géométrie_Chambranle - Position: Aucun; Épaisseur Chambranle intérieur: 0 cm; Longueur Chambranle intérieur: 0 cm; Superposition Chambranle intérieur: 0 cm; Épaisseur Intrados: 0 cm; Épaisseur Chambranle extérieur: 0 cm; Largeur Chambranle extérieur: 0 cm; Superposition Chambranle extérieur: 0 cm; Épaisseur Intrados extérieur: 0 cm
IFC_Pset_Géométrie_CORNICHE depuis profil - Position: Aucune; sets with these values: 2
IFC_Pset_Géométrie_CORNICHE Extérieure à partir d'un profil - Décalage: 0; Angle: 0 deg; Symétrie: no; Fermer: no; sets with these values: 2
IFC_Pset_Géométrie_BASE Extérieure à partir d'un profil - Angle: 0 deg; Symétrie: no; Côté: 0 cm; sets with these values: 2
IFC_Pset_Géométrie_1° MENUISERIE - Position: Extérieur; Décalage: 0 cm
IFC_Pset_Géométrie_2° MENUISERIE - Décalage: 0 cm
IFC_Pset_Géométrie - Côté extérieur: 0; Invertir (dte/gche): no; Invertir (intérieur/extérieur): no; Largeur: 79.0044 cm; Hauteur: 206.001 cm; Hauteur 2: 0 cm; Rayon Arc: 0 cm; Rayon Cercle: 0 cm; Demi-axe horizontal: 0 cm; Demi-axe vertical: 0 cm
IFC_Pset_Géométrie_GRILLE - décalage: 0 cm; Offset latéral: 0 cm; Décalage supérieur: 0 cm; Décalage inférieur: 0 cm; Nombre accrochages latéraux: 0; Nombre d'accrochages supérieurs: 0; Nombre accrochages inférieurs: 0
IFC_Pset_Système de Référence Altimétrique_INFÉRIEUR - NIVEAU: Rez-de-Jardin (Rez-de-Jardin 15545); delta: 0.601515 cm; sous Niveau: <aucun>
IFC_Pset_Données Métré - Surface 1re Menuiserie: 16300 cm2; Surface Vitre 1re Menuiserie: 0 cm2; Surface du Cadre de la 1re Menuiserie: 3600 cm2; Surface 2e Menuiserie: 0 cm2; Surface Vitre 2e Menuiserie: 0 cm2; Surface du Cadre de la 2ème Menuiserie: 0 cm2; Surface de l'Ouverture: 16300 cm2; Surface de l'Ébrasement: 0 cm2; Surface du Seuil: 0 cm2; Surface du Seuil intérieur: 0 cm2; Volume du seuil: 0 cm3; Volume du seuil intérieur: 0 cm3; Surface de la Grille: 0 cm2; Volume de la Grille: 0 cm3
IFC_Pset_Matériaux_1° MENUISERIE - Cadre externe: Bleu pastel; Panneau extérieur: Bleu pastel; Poignée: Aluminium satiné
Pset_DoorCommon - Reference: Porte_1VB[1P] (..\Porte classique\1 Vantail Battant\) <aucun>

# IfcDoor: Porte_1VB[1P], Porte 78424
In: Rez-de-Jardin
Type - OperationType: SINGLE_SWING_RIGHT; ParameterTakesPrecedence: yes; Sizeable: no; Material: Brèche oniciata, Aluminium satiné, Noyer 01
Type - IfcDoorLiningProperties - LiningDepth: 8 cm; LiningThickness: 3 cm
Type - IfcDoorPanelProperties - PanelDepth: 6 cm; PanelOperation: SWINGING; PanelWidth: 1; PanelPosition: RIGHT
Description: Porte; OverallHeight: 206 cm; OverallWidth: 91.1022 cm
__RECOGNIZE__ - ID: 78424; TPLG: 102; TPLG_OD: 9005; GENERATE: 1
CTLG_EXTERNAL_LINK - 0, DocType: 3; 0, Tag: 100; 0, Crc: -1099552363; 1, DocType: 5; 1, Tag: 700; 1, Crc: 1544883754; 2, DocType: 2; 2, Tag: 0; 2, Crc: -746779066; 3, DocType: 2; 3, Tag: 20; 3, Crc: 1141262141; 4, DocType: 2; 4, Tag: 102; 4, Crc: -990824515; 5, DocType: 2; 5, Tag: 105; 5, Crc: -990824515; 6, DocType: 2; 6, Tag: 107; 6, Crc: -212966465
IFC_PSET_PolygonOffset - polygonOffsetFactor: 2; polygonOffsetUnits: 2
IFC_Pset_Caractéristiques - ID: 78424; Numérotation: 35; Numéro niveau: 02; Titre niveau: Rez-de-Jardin; Modèle 1re menuiserie: Porte_1VB[1P]
IFC_Pset_Géométrie_Ébrasement - Présent: no; Côté supérieur: no; Côté INFÉRIEUR: no; Épaisseur extérieure: 0 cm; Épaisseur latérale gauche: 0 cm; Épaisseur latérale droite: 0 cm; Épiasseur latérale supérieure: 0 cm; Épaisseur diagonale gauche: 0 cm; Épaisseur diagonale droite: 0 cm; Épaisseur diagonale inférieure: 0 cm; Épaisseur diagonale supérieure: 0 cm; Épaisseur intérieur: 0 cm
IFC_Pset_Géométrie_Seuil - Type: Aucun; Épaisseur: 0 cm; Épaisseur interne: 0 cm; Décalage séparation: 0 cm; Appui extérieur: 0 cm; Appui intérieur: 0 cm; Côté latéral externe: 0 cm; Côté latéral interne: 0 cm
IFC_Pset_Géométrie_Chambranle - Position: Aucun; Épaisseur Chambranle intérieur: 0 cm; Longueur Chambranle intérieur: 0 cm; Superposition Chambranle intérieur: 0 cm; Épaisseur Intrados: 0 cm; Épaisseur Chambranle extérieur: 0 cm; Largeur Chambranle extérieur: 0 cm; Superposition Chambranle extérieur: 0 cm; Épaisseur Intrados extérieur: 0 cm
IFC_Pset_Géométrie_CORNICHE depuis profil - Position: Aucune
IFC_Pset_Géométrie_CORNICHE Extérieure à partir d'un profil - Décalage: 0; Angle: 0 deg; Symétrie: no; Fermer: no; sets with these values: 2
IFC_Pset_Géométrie_Base depuis profil - Position: Extérieur
IFC_Pset_Géométrie_BASE Extérieure à partir d'un profil - Profil: Base100x80mm (..\Base\); Décalage: [0,00; 0,00] mm; Angle: 90 deg; Symétrie: yes; Côté: 8 cm
IFC_Pset_Géométrie_BASE Intérieure à partir d'un profil - Angle: 0 deg; Symétrie: no; Côté: 0 cm
IFC_Pset_Géométrie_1° MENUISERIE - Position: Extérieur; Décalage: 7 cm
IFC_Pset_Géométrie_2° MENUISERIE - Décalage: 0 cm
IFC_Pset_Géométrie - Côté extérieur: 1; Invertir (dte/gche): no; Invertir (intérieur/extérieur): no; Largeur: 91.1022 cm; Hauteur: 206 cm; Hauteur 2: 0 cm; Rayon Arc: 0 cm; Rayon Cercle: 0 cm; Demi-axe horizontal: 0 cm; Demi-axe vertical: 0 cm
IFC_Pset_Géométrie_GRILLE - décalage: 0 cm; Offset latéral: 0 cm; Décalage supérieur: 0 cm; Décalage inférieur: 0 cm; Nombre accrochages latéraux: 0; Nombre d'accrochages supérieurs: 0; Nombre accrochages inférieurs: 0
IFC_Pset_Système de Référence Altimétrique_INFÉRIEUR - NIVEAU: Rez-de-Jardin (Rez-de-Jardin 15545); delta: 0.601515 cm; sous Niveau: <aucun>
IFC_Pset_Données Métré - Surface 1re Menuiserie: 18800 cm2; Surface Vitre 1re Menuiserie: 0 cm2; Surface du Cadre de la 1re Menuiserie: 3700 cm2; Surface 2e Menuiserie: 0 cm2; Surface Vitre 2e Menuiserie: 0 cm2; Surface du Cadre de la 2ème Menuiserie: 0 cm2; Surface de l'Ouverture: 18800 cm2; Surface de l'Ébrasement: 0 cm2; Surface du Seuil: 0 cm2; Surface du Seuil intérieur: 0 cm2; Volume du seuil: 0 cm3; Volume du seuil intérieur: 0 cm3; Surface de la Grille: 0 cm2; Volume de la Grille: 0 cm3
IFC_Pset_Matériaux - Base Externe: Brèche oniciata
IFC_Pset_Matériaux_1° MENUISERIE - Cadre externe: Noyer 01; Panneau extérieur: Noyer 01; Poignée: Aluminium satiné
Pset_DoorCommon - Reference: Porte_1VB[1P] (..\Porte classique\1 Vantail Battant\) <aucun>

# IfcDoor: Porte_1VB[1P], Porte 1533995
In: Niveau 2
Type - OperationType: SINGLE_SWING_RIGHT; ParameterTakesPrecedence: yes; Sizeable: no; Material: Béton (01), Aluminium satiné, Blanc gris
Type - IfcDoorLiningProperties - LiningDepth: 8 cm; LiningThickness: 3 cm; ThresholdDepth: 30 cm; ThresholdThickness: 3 cm
Type - IfcDoorPanelProperties - PanelDepth: 6 cm; PanelOperation: SWINGING; PanelWidth: 1; PanelPosition: RIGHT
Description: Porte; OverallHeight: 210 cm; OverallWidth: 88.5659 cm
__RECOGNIZE__ - ID: 1533995; TPLG: 102; TPLG_OD: 9005; GENERATE: 1
CTLG_EXTERNAL_LINK - 0, DocType: 3; 0, Tag: 100; 0, Crc: -1099552363; 1, DocType: 2; 1, Tag: 0; 1, Crc: -746779066; 2, DocType: 2; 2, Tag: 15; 2, Crc: -1434640612; 3, DocType: 2; 3, Tag: 102; 3, Crc: 1922095223; 4, DocType: 2; 4, Tag: 105; 4, Crc: 1922095223; 5, DocType: 2; 5, Tag: 107; 5, Crc: -212966465
IFC_PSET_PolygonOffset - polygonOffsetFactor: 2; polygonOffsetUnits: 2
IFC_Pset_Caractéristiques - ID: 1533995; Numérotation: 93; Numéro niveau: 05; Titre niveau: Niveau 2; Modèle 1re menuiserie: Porte_1VB[1P]
IFC_Pset_Géométrie_Ébrasement - Présent: no; Côté supérieur: no; Côté INFÉRIEUR: no; Épaisseur extérieure: 0 cm; Épaisseur latérale gauche: 0 cm; Épaisseur latérale droite: 0 cm; Épiasseur latérale supérieure: 0 cm; Épaisseur diagonale gauche: 0 cm; Épaisseur diagonale droite: 0 cm; Épaisseur diagonale inférieure: 0 cm; Épaisseur diagonale supérieure: 0 cm; Épaisseur intérieur: 0 cm
IFC_Pset_Géométrie_Seuil - Type: Unique; Épaisseur: 3 cm; Épaisseur interne: 3 cm; Décalage séparation: 0 cm; Appui extérieur: 21 cm; Appui intérieur: 0 cm; Côté latéral externe: 0 cm; Côté latéral interne: 5 cm
IFC_Pset_Géométrie_Chambranle - Position: Aucun; Épaisseur Chambranle intérieur: 0 cm; Longueur Chambranle intérieur: 0 cm; Superposition Chambranle intérieur: 0 cm; Épaisseur Intrados: 0 cm; Épaisseur Chambranle extérieur: 0 cm; Largeur Chambranle extérieur: 0 cm; Superposition Chambranle extérieur: 0 cm; Épaisseur Intrados extérieur: 0 cm
IFC_Pset_Géométrie_CORNICHE depuis profil - Position: Aucune; sets with these values: 2
IFC_Pset_Géométrie_CORNICHE Extérieure à partir d'un profil - Décalage: 0; Angle: 0 deg; Symétrie: no; Fermer: no; sets with these values: 2
IFC_Pset_Géométrie_BASE Extérieure à partir d'un profil - Angle: 0 deg; Symétrie: no; Côté: 0 cm; sets with these values: 2
IFC_Pset_Géométrie_1° MENUISERIE - Position: Intérieur; Décalage: 0 cm
IFC_Pset_Géométrie_2° MENUISERIE - Décalage: 0 cm
IFC_Pset_Géométrie - Côté extérieur: 0; Invertir (dte/gche): yes; Invertir (intérieur/extérieur): yes; Largeur: 88.5659 cm; Hauteur: 210 cm; Hauteur 2: 0 cm; Rayon Arc: 0 cm; Rayon Cercle: 0 cm; Demi-axe horizontal: 0 cm; Demi-axe vertical: 0 cm
IFC_Pset_Géométrie_GRILLE - décalage: 0 cm; Offset latéral: 0 cm; Décalage supérieur: 0 cm; Décalage inférieur: 0 cm; Nombre accrochages latéraux: 0; Nombre d'accrochages supérieurs: 0; Nombre accrochages inférieurs: 0
IFC_Pset_Système de Référence Altimétrique_INFÉRIEUR - NIVEAU: Niveau 2 (Niveau 2 13545); delta: 2 cm; sous Niveau: <aucun>
IFC_Pset_Données Métré - Surface 1re Menuiserie: 18600 cm2; Surface Vitre 1re Menuiserie: 0 cm2; Surface du Cadre de la 1re Menuiserie: 3800 cm2; Surface 2e Menuiserie: 0 cm2; Surface Vitre 2e Menuiserie: 0 cm2; Surface du Cadre de la 2ème Menuiserie: 0 cm2; Surface de l'Ouverture: 18600 cm2; Surface de l'Ébrasement: 0 cm2; Surface du Seuil: 2700 cm2; Surface du Seuil intérieur: 0 cm2; Volume du seuil: 10000 cm3; Volume du seuil intérieur: 10000 cm3; Surface de la Grille: 0 cm2; Volume de la Grille: 0 cm3
IFC_Pset_Matériaux - Seuil: Béton (01)
IFC_Pset_Matériaux_1° MENUISERIE - Cadre externe: Blanc gris; Panneau extérieur: Blanc gris; Poignée: Aluminium satiné
Pset_DoorCommon - Reference: Porte_1VB[1P] (..\Porte classique\1 Vantail Battant\) <aucun>

# IfcDoor: Porte_1VB[1P], Porte 780694
In: Niveau 2
Type - OperationType: SINGLE_SWING_RIGHT; ParameterTakesPrecedence: yes; Sizeable: no; Material: Béton (01), Aluminium satiné, Noyer 01
Type - IfcDoorLiningProperties - LiningDepth: 8 cm; LiningThickness: 3 cm; ThresholdDepth: 31 cm; ThresholdThickness: 3 cm
Type - IfcDoorPanelProperties - PanelDepth: 6 cm; PanelOperation: SWINGING; PanelWidth: 1; PanelPosition: RIGHT
Description: Porte; OverallHeight: 203.7 cm; OverallWidth: 79.2666 cm
__RECOGNIZE__ - ID: 780694; TPLG: 102; TPLG_OD: 9005; GENERATE: 1
CTLG_EXTERNAL_LINK - 0, DocType: 3; 0, Tag: 100; 0, Crc: -1099552363; 1, DocType: 2; 1, Tag: 0; 1, Crc: -746779066; 2, DocType: 2; 2, Tag: 15; 2, Crc: -1434640612; 3, DocType: 2; 3, Tag: 102; 3, Crc: -990824515; 4, DocType: 2; 4, Tag: 105; 4, Crc: -990824515; 5, DocType: 2; 5, Tag: 107; 5, Crc: -212966465
IFC_PSET_PolygonOffset - polygonOffsetFactor: 2; polygonOffsetUnits: 2
IFC_Pset_Caractéristiques - ID: 780694; Numérotation: 92; Numéro niveau: 05; Titre niveau: Niveau 2; Modèle 1re menuiserie: Porte_1VB[1P]
IFC_Pset_Géométrie_Ébrasement - Présent: no; Côté supérieur: no; Côté INFÉRIEUR: no; Épaisseur extérieure: 0 cm; Épaisseur latérale gauche: 0 cm; Épaisseur latérale droite: 0 cm; Épiasseur latérale supérieure: 0 cm; Épaisseur diagonale gauche: 0 cm; Épaisseur diagonale droite: 0 cm; Épaisseur diagonale inférieure: 0 cm; Épaisseur diagonale supérieure: 0 cm; Épaisseur intérieur: 0 cm
IFC_Pset_Géométrie_Seuil - Type: Unique; Épaisseur: 3 cm; Épaisseur interne: 3 cm; Décalage séparation: 0 cm; Appui extérieur: 21 cm; Appui intérieur: 0 cm; Côté latéral externe: 0 cm; Côté latéral interne: 5 cm
IFC_Pset_Géométrie_Chambranle - Position: Aucun; Épaisseur Chambranle intérieur: 0 cm; Longueur Chambranle intérieur: 0 cm; Superposition Chambranle intérieur: 0 cm; Épaisseur Intrados: 0 cm; Épaisseur Chambranle extérieur: 0 cm; Largeur Chambranle extérieur: 0 cm; Superposition Chambranle extérieur: 0 cm; Épaisseur Intrados extérieur: 0 cm
IFC_Pset_Géométrie_CORNICHE depuis profil - Position: Aucune; sets with these values: 2
IFC_Pset_Géométrie_CORNICHE Extérieure à partir d'un profil - Décalage: 0; Angle: 0 deg; Symétrie: no; Fermer: no; sets with these values: 2
IFC_Pset_Géométrie_BASE Extérieure à partir d'un profil - Angle: 0 deg; Symétrie: no; Côté: 0 cm; sets with these values: 2
IFC_Pset_Géométrie_1° MENUISERIE - Position: Intérieur; Décalage: 0 cm
IFC_Pset_Géométrie_2° MENUISERIE - Décalage: 0 cm
IFC_Pset_Géométrie - Côté extérieur: 0; Invertir (dte/gche): yes; Invertir (intérieur/extérieur): no; Largeur: 79.2666 cm; Hauteur: 203.7 cm; Hauteur 2: 0 cm; Rayon Arc: 0 cm; Rayon Cercle: 0 cm; Demi-axe horizontal: 0 cm; Demi-axe vertical: 0 cm
IFC_Pset_Géométrie_GRILLE - décalage: 0 cm; Offset latéral: 0 cm; Décalage supérieur: 0 cm; Décalage inférieur: 0 cm; Nombre accrochages latéraux: 0; Nombre d'accrochages supérieurs: 0; Nombre accrochages inférieurs: 0
IFC_Pset_Système de Référence Altimétrique_INFÉRIEUR - NIVEAU: Niveau 2 (Niveau 2 13545); delta: 1.42109e-12 cm; sous Niveau: <aucun>
IFC_Pset_Données Métré - Surface 1re Menuiserie: 16100 cm2; Surface Vitre 1re Menuiserie: 0 cm2; Surface du Cadre de la 1re Menuiserie: 3600 cm2; Surface 2e Menuiserie: 0 cm2; Surface Vitre 2e Menuiserie: 0 cm2; Surface du Cadre de la 2ème Menuiserie: 0 cm2; Surface de l'Ouverture: 16100 cm2; Surface de l'Ébrasement: 0 cm2; Surface du Seuil: 2500 cm2; Surface du Seuil intérieur: 0 cm2; Volume du seuil: 10000 cm3; Volume du seuil intérieur: 10000 cm3; Surface de la Grille: 0 cm2; Volume de la Grille: 0 cm3
IFC_Pset_Matériaux - Seuil: Béton (01)
IFC_Pset_Matériaux_1° MENUISERIE - Cadre externe: Noyer 01; Panneau extérieur: Noyer 01; Poignée: Aluminium satiné
Pset_DoorCommon - Reference: Porte_1VB[1P] (..\Porte classique\1 Vantail Battant\) <aucun>

# IfcDoor: Porte_1VB[1P] (2)
In: Rez-de-Jardin
Type - OperationType: SINGLE_SWING_RIGHT; ParameterTakesPrecedence: yes; Sizeable: no; Material: Gris de sécurité, Aluminium satiné
Type - IfcDoorLiningProperties - LiningDepth: 8 cm; LiningThickness: 3 cm
Type - IfcDoorPanelProperties - PanelDepth: 6 cm; PanelOperation: SWINGING; PanelWidth: 1; PanelPosition: RIGHT
Description: Porte
__RECOGNIZE__ - TPLG: 102; TPLG_OD: 9005; GENERATE: 1
CTLG_EXTERNAL_LINK - 0, DocType: 3; 0, Tag: 100; 0, Crc: -1099552363; 1, DocType: 2; 1, Tag: 0; 1, Crc: -746779066; 2, DocType: 2; 2, Tag: 102; 2, Crc: -205025647; 3, DocType: 2; 3, Tag: 105; 3, Crc: -205025647; 4, DocType: 2; 4, Tag: 107; 4, Crc: -212966465
IFC_PSET_PolygonOffset - polygonOffsetFactor: 2; polygonOffsetUnits: 2
IFC_Pset_Caractéristiques - Numéro niveau: 02; Titre niveau: Rez-de-Jardin; Modèle 1re menuiserie: Porte_1VB[1P]
IFC_Pset_Géométrie_Ébrasement - Présent: no; Côté supérieur: no; Côté INFÉRIEUR: no; Épaisseur extérieure: 0 cm; Épaisseur latérale gauche: 0 cm; Épaisseur latérale droite: 0 cm; Épiasseur latérale supérieure: 0 cm; Épaisseur diagonale gauche: 0 cm; Épaisseur diagonale droite: 0 cm; Épaisseur diagonale inférieure: 0 cm; Épaisseur diagonale supérieure: 0 cm; Épaisseur intérieur: 0 cm
IFC_Pset_Géométrie_Seuil - Type: Aucun; Épaisseur: 0 cm; Épaisseur interne: 0 cm; Décalage séparation: 0 cm; Appui extérieur: 0 cm; Appui intérieur: 0 cm; Côté latéral externe: 0 cm; Côté latéral interne: 0 cm
IFC_Pset_Géométrie_Chambranle - Position: Aucun; Épaisseur Chambranle intérieur: 0 cm; Longueur Chambranle intérieur: 0 cm; Superposition Chambranle intérieur: 0 cm; Épaisseur Intrados: 0 cm; Épaisseur Chambranle extérieur: 0 cm; Largeur Chambranle extérieur: 0 cm; Superposition Chambranle extérieur: 0 cm; Épaisseur Intrados extérieur: 0 cm
IFC_Pset_Géométrie_CORNICHE depuis profil - Position: Aucune; sets with these values: 2
IFC_Pset_Géométrie_CORNICHE Extérieure à partir d'un profil - Décalage: 0; Angle: 0 deg; Symétrie: no; Fermer: no; sets with these values: 2
IFC_Pset_Géométrie_BASE Extérieure à partir d'un profil - Angle: 0 deg; Symétrie: no; Côté: 0 cm; sets with these values: 2
IFC_Pset_Géométrie_1° MENUISERIE - Position: Intérieur; Décalage: 0 cm
IFC_Pset_Géométrie_2° MENUISERIE - Décalage: 0 cm
IFC_Pset_Géométrie - Côté extérieur: 0; Invertir (dte/gche): no; Invertir (intérieur/extérieur): no; Hauteur 2: 0 cm; Rayon Arc: 0 cm; Rayon Cercle: 0 cm; Demi-axe horizontal: 0 cm; Demi-axe vertical: 0 cm
IFC_Pset_Géométrie_GRILLE - décalage: 0 cm; Offset latéral: 0 cm; Décalage supérieur: 0 cm; Décalage inférieur: 0 cm; Nombre accrochages latéraux: 0; Nombre d'accrochages supérieurs: 0; Nombre accrochages inférieurs: 0
IFC_Pset_Système de Référence Altimétrique_INFÉRIEUR - NIVEAU: Rez-de-Jardin (Rez-de-Jardin 15545); sous Niveau: <aucun>
IFC_Pset_Données Métré - Surface Vitre 1re Menuiserie: 0 cm2; Surface 2e Menuiserie: 0 cm2; Surface Vitre 2e Menuiserie: 0 cm2; Surface du Cadre de la 2ème Menuiserie: 0 cm2; Surface de l'Ébrasement: 0 cm2; Surface du Seuil: 0 cm2; Surface du Seuil intérieur: 0 cm2; Volume du seuil: 0 cm3; Volume du seuil intérieur: 0 cm3; Surface de la Grille: 0 cm2; Volume de la Grille: 0 cm3
IFC_Pset_Matériaux_1° MENUISERIE - Cadre externe: Gris de sécurité; Panneau extérieur: Gris de sécurité; Poignée: Aluminium satiné
Pset_DoorCommon - Reference: Porte_1VB[1P] (..\Porte classique\1 Vantail Battant\) <aucun>
Name | OverallHeight (cm) = Hauteur (cm) | OverallWidth (cm) = Largeur (cm) | __RECOGNIZE__, ID = IFC_Pset_Caractéristiques, ID | Numérotation | delta (cm) | Surface 1re Menuiserie (cm2) = Surface de l'Ouverture (cm2) | Surface du Cadre de la 1re Menuiserie (cm2)
Porte 575944 | 206 | 93 | 575944 | 90 | 7.50511e-12 | 19200 | 3800
Porte 1702011 | 135.307 | 80 | 1702011 | 94 | 0.1 | 10800 | 2600

# IfcDoor: Porte_1VB[1P] (4)
Type - OperationType: SINGLE_SWING_RIGHT; ParameterTakesPrecedence: yes; Sizeable: no; Material: Gris lumière, Aluminium satiné
Type - IfcDoorLiningProperties - LiningDepth: 8 cm; LiningThickness: 3 cm
Type - IfcDoorPanelProperties - PanelDepth: 6 cm; PanelOperation: SWINGING; PanelWidth: 1; PanelPosition: RIGHT
Description: Porte
__RECOGNIZE__ - TPLG: 102; TPLG_OD: 9005; GENERATE: 1
CTLG_EXTERNAL_LINK - 0, DocType: 3; 0, Tag: 100; 0, Crc: -1099552363; 1, DocType: 2; 1, Tag: 0; 1, Crc: -746779066; 2, DocType: 2; 2, Tag: 102; 2, Crc: 1059052754; 3, DocType: 2; 3, Tag: 105; 3, Crc: 1059052754; 4, DocType: 2; 4, Tag: 107; 4, Crc: -212966465
IFC_PSET_PolygonOffset - polygonOffsetFactor: 2; polygonOffsetUnits: 2
IFC_Pset_Caractéristiques - Modèle 1re menuiserie: Porte_1VB[1P]
IFC_Pset_Géométrie_Ébrasement - Présent: no; Côté supérieur: no; Côté INFÉRIEUR: no; Épaisseur extérieure: 0 cm; Épaisseur latérale gauche: 0 cm; Épaisseur latérale droite: 0 cm; Épiasseur latérale supérieure: 0 cm; Épaisseur diagonale gauche: 0 cm; Épaisseur diagonale droite: 0 cm; Épaisseur diagonale inférieure: 0 cm; Épaisseur diagonale supérieure: 0 cm; Épaisseur intérieur: 0 cm
IFC_Pset_Géométrie_Seuil - Type: Aucun; Épaisseur: 0 cm; Épaisseur interne: 0 cm; Décalage séparation: 0 cm; Appui extérieur: 0 cm; Appui intérieur: 0 cm; Côté latéral externe: 0 cm; Côté latéral interne: 0 cm
IFC_Pset_Géométrie_Chambranle - Position: Aucun; Épaisseur Chambranle intérieur: 0 cm; Longueur Chambranle intérieur: 0 cm; Superposition Chambranle intérieur: 0 cm; Épaisseur Intrados: 0 cm; Épaisseur Chambranle extérieur: 0 cm; Largeur Chambranle extérieur: 0 cm; Superposition Chambranle extérieur: 0 cm; Épaisseur Intrados extérieur: 0 cm
IFC_Pset_Géométrie_CORNICHE depuis profil - Position: Aucune; sets with these values: 2
IFC_Pset_Géométrie_CORNICHE Extérieure à partir d'un profil - Décalage: 0; Angle: 0 deg; Symétrie: no; Fermer: no; sets with these values: 2
IFC_Pset_Géométrie_BASE Extérieure à partir d'un profil - Angle: 0 deg; Symétrie: no; Côté: 0 cm; sets with these values: 2
IFC_Pset_Géométrie_1° MENUISERIE - Décalage: 0 cm
IFC_Pset_Géométrie_2° MENUISERIE - Décalage: 0 cm
IFC_Pset_Géométrie - Invertir (intérieur/extérieur): yes; Hauteur 2: 0 cm; Rayon Arc: 0 cm; Rayon Cercle: 0 cm; Demi-axe horizontal: 0 cm; Demi-axe vertical: 0 cm
IFC_Pset_Géométrie_GRILLE - décalage: 0 cm; Offset latéral: 0 cm; Décalage supérieur: 0 cm; Décalage inférieur: 0 cm; Nombre accrochages latéraux: 0; Nombre d'accrochages supérieurs: 0; Nombre accrochages inférieurs: 0
IFC_Pset_Système de Référence Altimétrique_INFÉRIEUR - sous Niveau: <aucun>
IFC_Pset_Données Métré - Surface Vitre 1re Menuiserie: 0 cm2; Surface 2e Menuiserie: 0 cm2; Surface Vitre 2e Menuiserie: 0 cm2; Surface du Cadre de la 2ème Menuiserie: 0 cm2; Surface de l'Ébrasement: 0 cm2; Surface du Seuil: 0 cm2; Surface du Seuil intérieur: 0 cm2; Volume du seuil: 0 cm3; Volume du seuil intérieur: 0 cm3; Surface de la Grille: 0 cm2; Volume de la Grille: 0 cm3
IFC_Pset_Matériaux_1° MENUISERIE - Cadre externe: Gris lumière; Panneau extérieur: Gris lumière; Poignée: Aluminium satiné
Pset_DoorCommon - Reference: Porte_1VB[1P] (..\Porte classique\1 Vantail Battant\) <aucun>
Name | In | OverallHeight (cm) = Hauteur (cm) | OverallWidth (cm) = Largeur (cm) | __RECOGNIZE__, ID = IFC_Pset_Caractéristiques, ID | Numérotation | Numéro niveau | Titre niveau | Position | Côté extérieur | Invertir (dte/gche) | NIVEAU | delta (cm) | Surface 1re Menuiserie (cm2) = Surface de l'Ouverture (cm2) | Surface du Cadre de la 1re Menuiserie (cm2)
Porte 151475 | Niveau 2 | 203 | 74.6915 | 151475 | 69 | 05 | Niveau 2 | Extérieur | 0 | no | Niveau 2 (Niveau 2 13545) | 1.59872e-12 | 15200 | 3500
Porte 151474 | Niveau 2 | 203 | 74.7527 | 151474 | 68 | 05 | Niveau 2 | Extérieur | 1 | yes | Niveau 2 (Niveau 2 13545) | 1.77636e-12 | 15200 | 3500
Porte 151101 | Niveau 2 | 206 | 95.8906 | 151101 | 67 | 05 | Niveau 2 | Extérieur | 0 | no | Niveau 2 (Niveau 2 13545) | 1.06581e-12 | 19800 | 3800
Porte 197563 | Mezzanine | 204.703 | 84.1513 | 197563 | 78 | 06 | Mezzanine | Intérieur | 1 | no | Mezzanine (Mezzanine 49003) | 2 | 17200 | 3600

# IfcDoor: Porte_1VB[1P] (5)
In: Niveau 2
Type - OperationType: SINGLE_SWING_RIGHT; ParameterTakesPrecedence: yes; Sizeable: no; Material: Jaune 255-255-0, Aluminium satiné
Type - IfcDoorLiningProperties - LiningDepth: 8 cm; LiningThickness: 3 cm
Type - IfcDoorPanelProperties - PanelDepth: 6 cm; PanelOperation: SWINGING; PanelWidth: 1; PanelPosition: RIGHT
Description: Porte
__RECOGNIZE__ - TPLG: 102; TPLG_OD: 9005; GENERATE: 1
CTLG_EXTERNAL_LINK - 0, DocType: 3; 0, Tag: 100; 0, Crc: -1099552363; 1, DocType: 2; 1, Tag: 0; 1, Crc: -746779066; 2, DocType: 2; 2, Tag: 102; 2, Crc: -799740758; 3, DocType: 2; 3, Tag: 105; 3, Crc: -799740758; 4, DocType: 2; 4, Tag: 107; 4, Crc: -212966465
IFC_PSET_PolygonOffset - polygonOffsetFactor: 2; polygonOffsetUnits: 2
IFC_Pset_Caractéristiques - Numéro niveau: 05; Titre niveau: Niveau 2; Modèle 1re menuiserie: Porte_1VB[1P]
IFC_Pset_Géométrie_Ébrasement - Présent: no; Côté supérieur: no; Côté INFÉRIEUR: no; Épaisseur extérieure: 0 cm; Épaisseur latérale gauche: 0 cm; Épaisseur latérale droite: 0 cm; Épiasseur latérale supérieure: 0 cm; Épaisseur diagonale gauche: 0 cm; Épaisseur diagonale droite: 0 cm; Épaisseur diagonale inférieure: 0 cm; Épaisseur diagonale supérieure: 0 cm; Épaisseur intérieur: 0 cm
IFC_Pset_Géométrie_Seuil - Type: Aucun; Épaisseur: 0 cm; Épaisseur interne: 0 cm; Décalage séparation: 0 cm; Appui extérieur: 0 cm; Appui intérieur: 0 cm; Côté latéral externe: 0 cm; Côté latéral interne: 0 cm
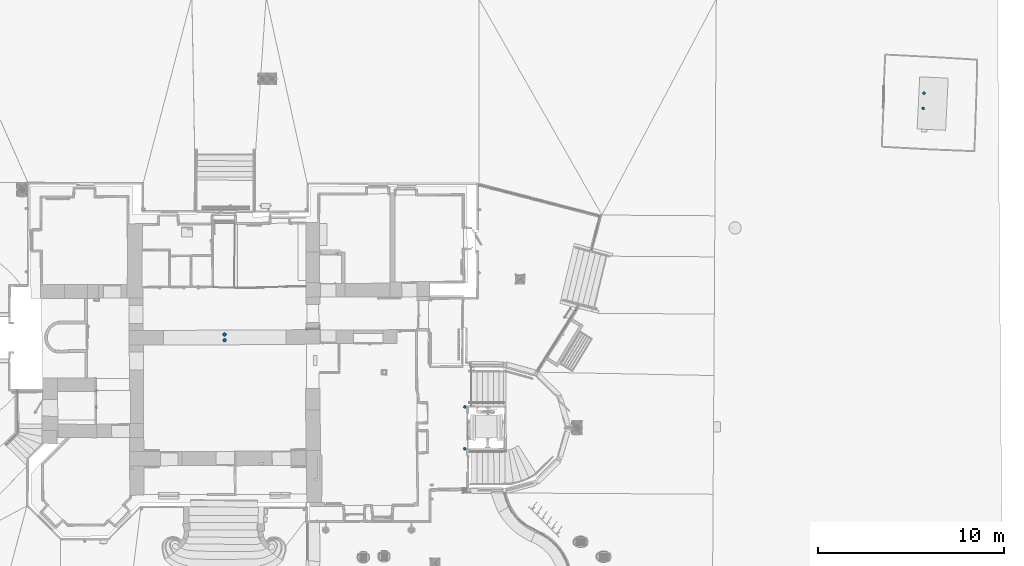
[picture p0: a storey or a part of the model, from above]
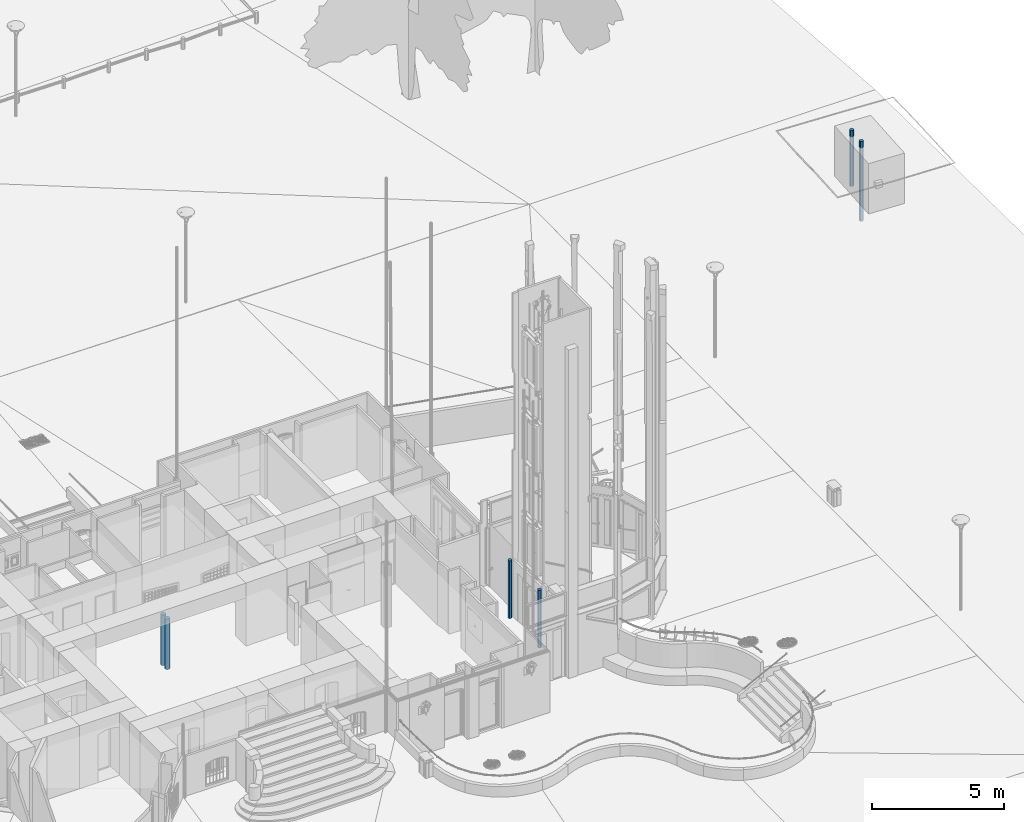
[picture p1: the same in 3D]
Properties of the parts of a building model (IFC2X3), part 7 of 37

# IfcDoor: Porte_1VB[1P] (5)
IFC_Pset_Géométrie_Chambranle - Position: Aucun; Épaisseur Chambranle intérieur: 0 cm; Longueur Chambranle intérieur: 0 cm; Superposition Chambranle intérieur: 0 cm; Épaisseur Intrados: 0 cm; Épaisseur Chambranle extérieur: 0 cm; Largeur Chambranle extérieur: 0 cm; Superposition Chambranle extérieur: 0 cm; Épaisseur Intrados extérieur: 0 cm
IFC_Pset_Géométrie_CORNICHE depuis profil - Position: Aucune; sets with these values: 2
IFC_Pset_Géométrie_CORNICHE Extérieure à partir d'un profil - Décalage: 0; Angle: 0 deg; Symétrie: no; Fermer: no; sets with these values: 2
IFC_Pset_Géométrie_BASE Extérieure à partir d'un profil - Angle: 0 deg; Symétrie: no; Côté: 0 cm; sets with these values: 2
IFC_Pset_Géométrie_2° MENUISERIE - Décalage: 0 cm
IFC_Pset_Géométrie - Hauteur 2: 0 cm; Rayon Arc: 0 cm; Rayon Cercle: 0 cm; Demi-axe horizontal: 0 cm; Demi-axe vertical: 0 cm
IFC_Pset_Géométrie_GRILLE - décalage: 0 cm; Offset latéral: 0 cm; Décalage supérieur: 0 cm; Décalage inférieur: 0 cm; Nombre accrochages latéraux: 0; Nombre d'accrochages supérieurs: 0; Nombre accrochages inférieurs: 0
IFC_Pset_Système de Référence Altimétrique_INFÉRIEUR - NIVEAU: Niveau 2 (Niveau 2 13545); sous Niveau: <aucun>
IFC_Pset_Données Métré - Surface Vitre 1re Menuiserie: 0 cm2; Surface du Cadre de la 1re Menuiserie: 3800 cm2; Surface 2e Menuiserie: 0 cm2; Surface Vitre 2e Menuiserie: 0 cm2; Surface du Cadre de la 2ème Menuiserie: 0 cm2; Surface de l'Ébrasement: 0 cm2; Surface du Seuil: 0 cm2; Surface du Seuil intérieur: 0 cm2; Volume du seuil: 0 cm3; Volume du seuil intérieur: 0 cm3; Surface de la Grille: 0 cm2; Volume de la Grille: 0 cm3
IFC_Pset_Matériaux_1° MENUISERIE - Cadre externe: Jaune 255-255-0; Panneau extérieur: Jaune 255-255-0; Poignée: Aluminium satiné
Pset_DoorCommon - Reference: Porte_1VB[1P] (..\Porte classique\1 Vantail Battant\) <aucun>
Name | OverallHeight (cm) = Hauteur (cm) | OverallWidth (cm) = Largeur (cm) | __RECOGNIZE__, ID = IFC_Pset_Caractéristiques, ID | Numérotation | Position | Décalage (cm) | Côté extérieur | Invertir (dte/gche) | Invertir (intérieur/extérieur) | delta (cm) | Surface 1re Menuiserie (cm2) = Surface de l'Ouverture (cm2)
Porte 177561 | 208 | 94.561 | 177561 | 77 | Extérieur | 6 | 1 | no | no | 1.82077e-12 | 19700
Porte 152384 | 207 | 94.6708 | 152384 | 71 | Centre | 0 | 1 | no | no | 1.42109e-12 | 19600
Porte 158764 | 208.5 | 97.2291 | 158764 | 73 | Extérieur | 0 | 0 | yes | no | 3.55271e-13 | 20300
Porte 176758 | 207 | 95.8094 | 176758 | 76 | Centre | 0 | 1 | no | yes | 1.02141e-12 | 19800
Porte 168122 | 210 | 95.9995 | 168122 | 74 | Extérieur | 1.5 | 0 | yes | no | 0 | 20200

# IfcDoor: Porte_1VB[1P], Porte 78036
In: Rez-de-Jardin
Type - OperationType: SINGLE_SWING_RIGHT; ParameterTakesPrecedence: yes; Sizeable: no; Material: Vert clair_porte, Aluminium satiné
Type - IfcDoorLiningProperties - LiningDepth: 8 cm; LiningThickness: 3 cm
Type - IfcDoorPanelProperties - PanelDepth: 6 cm; PanelOperation: SWINGING; PanelWidth: 1; PanelPosition: RIGHT
Description: Porte; OverallHeight: 205 cm; OverallWidth: 82.0593 cm
__RECOGNIZE__ - ID: 78036; TPLG: 102; TPLG_OD: 9005; GENERATE: 1
CTLG_EXTERNAL_LINK - 0, DocType: 3; 0, Tag: 100; 0, Crc: -1099552363; 1, DocType: 2; 1, Tag: 0; 1, Crc: -746779066; 2, DocType: 2; 2, Tag: 102; 2, Crc: -1022614176; 3, DocType: 2; 3, Tag: 105; 3, Crc: -1022614176; 4, DocType: 2; 4, Tag: 107; 4, Crc: -212966465
IFC_PSET_PolygonOffset - polygonOffsetFactor: 2; polygonOffsetUnits: 2
IFC_Pset_Caractéristiques - ID: 78036; Numérotation: 33; Numéro niveau: 02; Titre niveau: Rez-de-Jardin; Modèle 1re menuiserie: Porte_1VB[1P]
IFC_Pset_Géométrie_Ébrasement - Présent: no; Côté supérieur: no; Côté INFÉRIEUR: no; Épaisseur extérieure: 0 cm; Épaisseur latérale gauche: 0 cm; Épaisseur latérale droite: 0 cm; Épiasseur latérale supérieure: 0 cm; Épaisseur diagonale gauche: 0 cm; Épaisseur diagonale droite: 0 cm; Épaisseur diagonale inférieure: 0 cm; Épaisseur diagonale supérieure: 0 cm; Épaisseur intérieur: 0 cm
IFC_Pset_Géométrie_Seuil - Type: Aucun; Épaisseur: 0 cm; Épaisseur interne: 0 cm; Décalage séparation: 0 cm; Appui extérieur: 0 cm; Appui intérieur: 0 cm; Côté latéral externe: 0 cm; Côté latéral interne: 0 cm
IFC_Pset_Géométrie_Chambranle - Position: Aucun; Épaisseur Chambranle intérieur: 0 cm; Longueur Chambranle intérieur: 0 cm; Superposition Chambranle intérieur: 0 cm; Épaisseur Intrados: 0 cm; Épaisseur Chambranle extérieur: 0 cm; Largeur Chambranle extérieur: 0 cm; Superposition Chambranle extérieur: 0 cm; Épaisseur Intrados extérieur: 0 cm
IFC_Pset_Géométrie_CORNICHE depuis profil - Position: Aucune; sets with these values: 2
IFC_Pset_Géométrie_CORNICHE Extérieure à partir d'un profil - Décalage: 0; Angle: 0 deg; Symétrie: no; Fermer: no; sets with these values: 2
IFC_Pset_Géométrie_BASE Extérieure à partir d'un profil - Angle: 0 deg; Symétrie: no; Côté: 0 cm; sets with these values: 2
IFC_Pset_Géométrie_1° MENUISERIE - Position: Extérieur; Décalage: 0 cm
IFC_Pset_Géométrie_2° MENUISERIE - Décalage: 0 cm
IFC_Pset_Géométrie - Côté extérieur: 1; Invertir (dte/gche): no; Invertir (intérieur/extérieur): no; Largeur: 82.0593 cm; Hauteur: 205 cm; Hauteur 2: 0 cm; Rayon Arc: 0 cm; Rayon Cercle: 0 cm; Demi-axe horizontal: 0 cm; Demi-axe vertical: 0 cm
IFC_Pset_Géométrie_GRILLE - décalage: 0 cm; Offset latéral: 0 cm; Décalage supérieur: 0 cm; Décalage inférieur: 0 cm; Nombre accrochages latéraux: 0; Nombre d'accrochages supérieurs: 0; Nombre accrochages inférieurs: 0
IFC_Pset_Système de Référence Altimétrique_INFÉRIEUR - NIVEAU: Rez-de-Jardin (Rez-de-Jardin 15545); delta: 2 cm; sous Niveau: <aucun>
IFC_Pset_Données Métré - Surface 1re Menuiserie: 16800 cm2; Surface Vitre 1re Menuiserie: 0 cm2; Surface du Cadre de la 1re Menuiserie: 3600 cm2; Surface 2e Menuiserie: 0 cm2; Surface Vitre 2e Menuiserie: 0 cm2; Surface du Cadre de la 2ème Menuiserie: 0 cm2; Surface de l'Ouverture: 16800 cm2; Surface de l'Ébrasement: 0 cm2; Surface du Seuil: 0 cm2; Surface du Seuil intérieur: 0 cm2; Volume du seuil: 0 cm3; Volume du seuil intérieur: 0 cm3; Surface de la Grille: 0 cm2; Volume de la Grille: 0 cm3
IFC_Pset_Matériaux_1° MENUISERIE - Cadre externe: Vert clair_porte; Panneau extérieur: Vert clair_porte; Poignée: Aluminium satiné
Pset_DoorCommon - Reference: Porte_1VB[1P] (..\Porte classique\1 Vantail Battant\) <aucun>

# IfcDoor: Porte_1VB[2P] (13)
In: Rez-de-chaussée
Type - ParameterTakesPrecedence: no; Sizeable: no; Material: Transparent, Aluminium satiné, Blanc trafic
Type - IfcDoorLiningProperties - LiningDepth: 8 cm; LiningThickness: 3 cm
Description: Porte
__RECOGNIZE__ - TPLG: 102; TPLG_OD: 9005; GENERATE: 1
CTLG_EXTERNAL_LINK - 0, DocType: 3; 0, Tag: 100; 0, Crc: 363241230; 1, DocType: 2; 1, Tag: 0; 1, Crc: -746779066; 2, DocType: 2; 2, Tag: 102; 2, Crc: -848491367; 3, DocType: 2; 3, Tag: 104; 3, Crc: -623492449; 4, DocType: 2; 4, Tag: 105; 4, Crc: -848491367; 5, DocType: 2; 5, Tag: 107; 5, Crc: 1305662025
IFC_PSET_PolygonOffset - polygonOffsetFactor: 2; polygonOffsetUnits: 2
IFC_Pset_Caractéristiques - Numéro niveau: 03; Titre niveau: Rez-de-chaussée; Modèle 1re menuiserie: Porte_1VB[2P]
IFC_Pset_Géométrie_Ébrasement - Présent: no; Côté supérieur: no; Côté INFÉRIEUR: no; Épaisseur extérieure: 0 cm; Épaisseur latérale gauche: 0 cm; Épaisseur latérale droite: 0 cm; Épiasseur latérale supérieure: 0 cm; Épaisseur diagonale gauche: 0 cm; Épaisseur diagonale droite: 0 cm; Épaisseur diagonale inférieure: 0 cm; Épaisseur diagonale supérieure: 0 cm; Épaisseur intérieur: 0 cm
IFC_Pset_Géométrie_Seuil - Type: Aucun; Épaisseur: 0 cm; Épaisseur interne: 0 cm; Décalage séparation: 0 cm; Appui extérieur: 0 cm; Appui intérieur: 0 cm; Côté latéral externe: 0 cm; Côté latéral interne: 0 cm
IFC_Pset_Géométrie_Chambranle - Position: Aucun; Épaisseur Chambranle intérieur: 0 cm; Longueur Chambranle intérieur: 0 cm; Superposition Chambranle intérieur: 0 cm; Épaisseur Intrados: 0 cm; Épaisseur Chambranle extérieur: 0 cm; Largeur Chambranle extérieur: 0 cm; Superposition Chambranle extérieur: 0 cm; Épaisseur Intrados extérieur: 0 cm
IFC_Pset_Géométrie_CORNICHE depuis profil - Position: Aucune; sets with these values: 2
IFC_Pset_Géométrie_CORNICHE Extérieure à partir d'un profil - Décalage: 0; Angle: 0 deg; Symétrie: no; Fermer: no; sets with these values: 2
IFC_Pset_Géométrie_BASE Extérieure à partir d'un profil - Angle: 0 deg; Symétrie: no; Côté: 0 cm; sets with these values: 2
IFC_Pset_Géométrie_1° MENUISERIE - Décalage: 0 cm
IFC_Pset_Géométrie_2° MENUISERIE - Décalage: 0 cm
IFC_Pset_Géométrie - Hauteur 2: 0 cm; Rayon Arc: 0 cm; Rayon Cercle: 0 cm; Demi-axe horizontal: 0 cm; Demi-axe vertical: 0 cm
IFC_Pset_Géométrie_GRILLE - décalage: 0 cm; Offset latéral: 0 cm; Décalage supérieur: 0 cm; Décalage inférieur: 0 cm; Nombre accrochages latéraux: 0; Nombre d'accrochages supérieurs: 0; Nombre accrochages inférieurs: 0
IFC_Pset_Système de Référence Altimétrique_INFÉRIEUR - NIVEAU: Rez-de-chaussée (Rez-de-chaussée 1047); sous Niveau: <aucun>
IFC_Pset_Données Métré - Surface 2e Menuiserie: 0 cm2; Surface Vitre 2e Menuiserie: 0 cm2; Surface du Cadre de la 2ème Menuiserie: 0 cm2; Surface de l'Ébrasement: 0 cm2; Surface du Seuil: 0 cm2; Surface du Seuil intérieur: 0 cm2; Volume du seuil: 0 cm3; Volume du seuil intérieur: 0 cm3; Surface de la Grille: 0 cm2; Volume de la Grille: 0 cm3
IFC_Pset_Matériaux_1° MENUISERIE - Cadre externe: Blanc trafic; Verre: Transparent; Panneau extérieur: Blanc trafic; Poignée: Aluminium satiné
Pset_DoorCommon - Reference: Porte_1VB[2P] (..\Porte moderne\1 Vantail Battant\) <aucun>
Name | OverallHeight (cm) = Hauteur (cm) | OverallWidth (cm) = Largeur (cm) | __RECOGNIZE__, ID = IFC_Pset_Caractéristiques, ID | Numérotation | Position | Côté extérieur | Invertir (dte/gche) | Invertir (intérieur/extérieur) | delta (cm) | Surface 1re Menuiserie (cm2) = Surface de l'Ouverture (cm2) | Surface Vitre 1re Menuiserie (cm2) | Surface du Cadre de la 1re Menuiserie (cm2)
Porte 26435 | 206 | 93 | 26435 | 05 | Intérieur | 1 | no | yes | 0.0128504 | 19200 | 13100 | 3800
Porte 30034 | 206 | 93.2467 | 30034 | 06 | Extérieur | 0 | yes | yes | 0.0128504 | 19200 | 13100 | 3800
Porte 31319 | 207 | 92.9766 | 31319 | 08 | Extérieur | 0 | no | no | 0.571732 | 19200 | 13200 | 3800
Porte 34088 | 203.665 | 88.4982 | 34088 | 15 | Extérieur | 0 | yes | yes | 0.0128504 | 18000 | 12200 | 3700
Porte 30041 | 208 | 88.0286 | 30041 | 07 | Extérieur | 0 | no | yes | 0.0128504 | 18300 | 12400 | 3700
Porte 31320 | 203 | 85.2347 | 31320 | 09 | Extérieur | 0 | no | yes | 0.0128504 | 17300 | 11600 | 3600
Porte 33565 | 203 | 82.9871 | 33565 | 13 | Extérieur | 0 | no | no | 0.0128504 | 16800 | 11300 | 3600
Porte 34091 | 208.39 | 95 | 34091 | 16 | Extérieur | 0 | yes | no | 0.0128504 | 19800 | 13600 | 3800
Porte 33319 | 203 | 95.3794 | 33319 | 12 | Extérieur | 1 | no | yes | 0.0128504 | 19400 | 13300 | 3700
Porte 33937 | 202.469 | 81.4205 | 33937 | 14 | Extérieur | 1 | no | no | 0.0128504 | 16500 | 11000 | 3600
Porte 23825 | 210 | 95.7421 | 23825 | 02 | Extérieur | 0 | yes | no | 0.0128504 | 20100 | 13800 | 3800
Porte 33313 | 203 | 74 | 33313 | 10 | Extérieur | 1 | no | no | 0.0128504 | 15000 | 9800 | 3500
Porte 33316 | 203 | 70 | 33316 | 11 | Extérieur | 1 | yes | no | 0.0128504 | 14200 | 9100 | 3500

# IfcDoor: Porte_1VB[2P] (2)
In: Rez-de-Jardin
Type - ParameterTakesPrecedence: no; Sizeable: no; Material: Transparent, Aluminium satiné, Blanc trafic, Rouge brillant
Type - IfcDoorLiningProperties - LiningDepth: 8 cm; LiningThickness: 3 cm
Description: Porte
__RECOGNIZE__ - TPLG: 102; TPLG_OD: 9005; GENERATE: 1
CTLG_EXTERNAL_LINK - 0, DocType: 3; 0, Tag: 100; 0, Crc: 363241230; 1, DocType: 2; 1, Tag: 0; 1, Crc: -746779066; 2, DocType: 2; 2, Tag: 102; 2, Crc: 2081975812; 3, DocType: 2; 3, Tag: 104; 3, Crc: -623492449; 4, DocType: 2; 4, Tag: 105; 4, Crc: -848491367; 5, DocType: 2; 5, Tag: 107; 5, Crc: 1305662025
IFC_PSET_PolygonOffset - polygonOffsetFactor: 2; polygonOffsetUnits: 2
IFC_Pset_Caractéristiques - Numéro niveau: 02; Titre niveau: Rez-de-Jardin; Modèle 1re menuiserie: Porte_1VB[2P]
IFC_Pset_Géométrie_Ébrasement - Présent: no; Côté supérieur: no; Côté INFÉRIEUR: no; Épaisseur extérieure: 0 cm; Épaisseur latérale gauche: 0 cm; Épaisseur latérale droite: 0 cm; Épiasseur latérale supérieure: 0 cm; Épaisseur diagonale gauche: 0 cm; Épaisseur diagonale droite: 0 cm; Épaisseur diagonale inférieure: 0 cm; Épaisseur diagonale supérieure: 0 cm; Épaisseur intérieur: 0 cm
IFC_Pset_Géométrie_Seuil - Type: Aucun; Épaisseur: 0 cm; Épaisseur interne: 0 cm; Décalage séparation: 0 cm; Appui extérieur: 0 cm; Appui intérieur: 0 cm; Côté latéral externe: 0 cm; Côté latéral interne: 0 cm
IFC_Pset_Géométrie_Chambranle - Position: Aucun; Épaisseur Chambranle intérieur: 0 cm; Longueur Chambranle intérieur: 0 cm; Superposition Chambranle intérieur: 0 cm; Épaisseur Intrados: 0 cm; Épaisseur Chambranle extérieur: 0 cm; Largeur Chambranle extérieur: 0 cm; Superposition Chambranle extérieur: 0 cm; Épaisseur Intrados extérieur: 0 cm
IFC_Pset_Géométrie_CORNICHE depuis profil - Position: Aucune; sets with these values: 2
IFC_Pset_Géométrie_CORNICHE Extérieure à partir d'un profil - Décalage: 0; Angle: 0 deg; Symétrie: no; Fermer: no; sets with these values: 2
IFC_Pset_Géométrie_BASE Extérieure à partir d'un profil - Angle: 0 deg; Symétrie: no; Côté: 0 cm; sets with these values: 2
IFC_Pset_Géométrie_1° MENUISERIE - Position: Extérieur
IFC_Pset_Géométrie_2° MENUISERIE - Décalage: 0 cm
IFC_Pset_Géométrie - Côté extérieur: 1; Invertir (intérieur/extérieur): no; Hauteur 2: 0 cm; Rayon Arc: 0 cm; Rayon Cercle: 0 cm; Demi-axe horizontal: 0 cm; Demi-axe vertical: 0 cm
IFC_Pset_Géométrie_GRILLE - décalage: 0 cm; Offset latéral: 0 cm; Décalage supérieur: 0 cm; Décalage inférieur: 0 cm; Nombre accrochages latéraux: 0; Nombre d'accrochages supérieurs: 0; Nombre accrochages inférieurs: 0
IFC_Pset_Système de Référence Altimétrique_INFÉRIEUR - NIVEAU: Rez-de-Jardin (Rez-de-Jardin 15545); delta: 0 cm; sous Niveau: <aucun>
IFC_Pset_Données Métré - Surface du Cadre de la 1re Menuiserie: 3900 cm2; Surface 2e Menuiserie: 0 cm2; Surface Vitre 2e Menuiserie: 0 cm2; Surface du Cadre de la 2ème Menuiserie: 0 cm2; Surface de l'Ébrasement: 0 cm2; Surface du Seuil: 0 cm2; Surface du Seuil intérieur: 0 cm2; Volume du seuil: 0 cm3; Volume du seuil intérieur: 0 cm3; Surface de la Grille: 0 cm2; Volume de la Grille: 0 cm3
IFC_Pset_Matériaux_1° MENUISERIE - Cadre externe: Rouge brillant; Verre: Transparent; Panneau extérieur: Blanc trafic; Poignée: Aluminium satiné
Pset_DoorCommon - Reference: Porte_1VB[2P] (..\Porte moderne\1 Vantail Battant\) <aucun>
Name | OverallHeight (cm) = Hauteur (cm) | OverallWidth (cm) = Largeur (cm) | __RECOGNIZE__, ID = IFC_Pset_Caractéristiques, ID | Numérotation | Décalage (cm) | Invertir (dte/gche) | Surface 1re Menuiserie (cm2) = Surface de l'Ouverture (cm2) | Surface Vitre 1re Menuiserie (cm2)
Porte 73997 | 214 | 97.0526 | 73997 | 23 | -12 | yes | 20800 | 14300
Porte 74001 | 213 | 98.1 | 74001 | 24 | 0 | no | 20900 | 14400

# IfcDoor: Porte_1VB[2P], Porte 23883
In: Rez-de-chaussée
Type - ParameterTakesPrecedence: no; Sizeable: no; Material: Transparent, Noyer 01, Aluminium satiné, Blanc trafic
Type - IfcDoorLiningProperties - LiningDepth: 8 cm; LiningThickness: 3 cm
Description: Porte; OverallHeight: 211 cm; OverallWidth: 77 cm
__RECOGNIZE__ - ID: 23883; TPLG: 102; TPLG_OD: 9005; GENERATE: 1
CTLG_EXTERNAL_LINK - 0, DocType: 3; 0, Tag: 100; 0, Crc: 363241230; 1, DocType: 2; 1, Tag: 0; 1, Crc: -746779066; 2, DocType: 2; 2, Tag: 102; 2, Crc: -848491367; 3, DocType: 2; 3, Tag: 104; 3, Crc: -623492449; 4, DocType: 2; 4, Tag: 105; 4, Crc: -990824515; 5, DocType: 2; 5, Tag: 107; 5, Crc: 1305662025
IFC_PSET_PolygonOffset - polygonOffsetFactor: 2; polygonOffsetUnits: 2
IFC_Pset_Caractéristiques - ID: 23883; Numérotation: 04; Numéro niveau: 03; Titre niveau: Rez-de-chaussée; Modèle 1re menuiserie: Porte_1VB[2P]
IFC_Pset_Géométrie_Ébrasement - Présent: no; Côté supérieur: no; Côté INFÉRIEUR: no; Épaisseur extérieure: 0 cm; Épaisseur latérale gauche: 0 cm; Épaisseur latérale droite: 0 cm; Épiasseur latérale supérieure: 0 cm; Épaisseur diagonale gauche: 0 cm; Épaisseur diagonale droite: 0 cm; Épaisseur diagonale inférieure: 0 cm; Épaisseur diagonale supérieure: 0 cm; Épaisseur intérieur: 0 cm
IFC_Pset_Géométrie_Seuil - Type: Aucun; Épaisseur: 0 cm; Épaisseur interne: 0 cm; Décalage séparation: 0 cm; Appui extérieur: 0 cm; Appui intérieur: 0 cm; Côté latéral externe: 0 cm; Côté latéral interne: 0 cm
IFC_Pset_Géométrie_Chambranle - Position: Aucun; Épaisseur Chambranle intérieur: 0 cm; Longueur Chambranle intérieur: 0 cm; Superposition Chambranle intérieur: 0 cm; Épaisseur Intrados: 0 cm; Épaisseur Chambranle extérieur: 0 cm; Largeur Chambranle extérieur: 0 cm; Superposition Chambranle extérieur: 0 cm; Épaisseur Intrados extérieur: 0 cm
IFC_Pset_Géométrie_CORNICHE depuis profil - Position: Aucune; sets with these values: 2
IFC_Pset_Géométrie_CORNICHE Extérieure à partir d'un profil - Décalage: 0; Angle: 0 deg; Symétrie: no; Fermer: no; sets with these values: 2
IFC_Pset_Géométrie_BASE Extérieure à partir d'un profil - Angle: 0 deg; Symétrie: no; Côté: 0 cm; sets with these values: 2
IFC_Pset_Géométrie_1° MENUISERIE - Position: Intérieur; Décalage: 0 cm
IFC_Pset_Géométrie_2° MENUISERIE - Décalage: 0 cm
IFC_Pset_Géométrie - Côté extérieur: 1; Invertir (dte/gche): yes; Invertir (intérieur/extérieur): yes; Largeur: 77 cm; Hauteur: 211 cm; Hauteur 2: 0 cm; Rayon Arc: 0 cm; Rayon Cercle: 0 cm; Demi-axe horizontal: 0 cm; Demi-axe vertical: 0 cm
IFC_Pset_Géométrie_GRILLE - décalage: 0 cm; Offset latéral: 0 cm; Décalage supérieur: 0 cm; Décalage inférieur: 0 cm; Nombre accrochages latéraux: 0; Nombre d'accrochages supérieurs: 0; Nombre accrochages inférieurs: 0
IFC_Pset_Système de Référence Altimétrique_INFÉRIEUR - NIVEAU: Rez-de-chaussée (Rez-de-chaussée 1047); delta: 0.0128504 cm; sous Niveau: <aucun>
IFC_Pset_Données Métré - Surface 1re Menuiserie: 16200 cm2; Surface Vitre 1re Menuiserie: 10700 cm2; Surface du Cadre de la 1re Menuiserie: 3600 cm2; Surface 2e Menuiserie: 0 cm2; Surface Vitre 2e Menuiserie: 0 cm2; Surface du Cadre de la 2ème Menuiserie: 0 cm2; Surface de l'Ouverture: 16200 cm2; Surface de l'Ébrasement: 0 cm2; Surface du Seuil: 0 cm2; Surface du Seuil intérieur: 0 cm2; Volume du seuil: 0 cm3; Volume du seuil intérieur: 0 cm3; Surface de la Grille: 0 cm2; Volume de la Grille: 0 cm3
IFC_Pset_Matériaux_1° MENUISERIE - Cadre externe: Blanc trafic; Verre: Transparent; Panneau extérieur: Noyer 01; Poignée: Aluminium satiné
Pset_DoorCommon - Reference: Porte_1VB[2P] (..\Porte moderne\1 Vantail Battant\) <aucun>

# IfcDoor: Porte_1VB[2P], Porte 73508
In: Rez-de-Jardin
Type - ParameterTakesPrecedence: no; Sizeable: no; Material: Transparent, Vert clair_porte, Aluminium satiné
Type - IfcDoorLiningProperties - LiningDepth: 8 cm; LiningThickness: 3 cm
Description: Porte; OverallHeight: 205 cm; OverallWidth: 93.7891 cm
__RECOGNIZE__ - ID: 73508; TPLG: 102; TPLG_OD: 9005; GENERATE: 1
CTLG_EXTERNAL_LINK - 0, DocType: 3; 0, Tag: 100; 0, Crc: 363241230; 1, DocType: 2; 1, Tag: 0; 1, Crc: -746779066; 2, DocType: 2; 2, Tag: 102; 2, Crc: -1022614176; 3, DocType: 2; 3, Tag: 104; 3, Crc: -623492449; 4, DocType: 2; 4, Tag: 105; 4, Crc: -1022614176; 5, DocType: 2; 5, Tag: 107; 5, Crc: 1305662025
IFC_PSET_PolygonOffset - polygonOffsetFactor: 2; polygonOffsetUnits: 2
IFC_Pset_Caractéristiques - ID: 73508; Numérotation: 19; Numéro niveau: 02; Titre niveau: Rez-de-Jardin; Modèle 1re menuiserie: Porte_1VB[2P]
IFC_Pset_Géométrie_Ébrasement - Présent: no; Côté supérieur: no; Côté INFÉRIEUR: no; Épaisseur extérieure: 0 cm; Épaisseur latérale gauche: 0 cm; Épaisseur latérale droite: 0 cm; Épiasseur latérale supérieure: 0 cm; Épaisseur diagonale gauche: 0 cm; Épaisseur diagonale droite: 0 cm; Épaisseur diagonale inférieure: 0 cm; Épaisseur diagonale supérieure: 0 cm; Épaisseur intérieur: 0 cm
IFC_Pset_Géométrie_Seuil - Type: Aucun; Épaisseur: 0 cm; Épaisseur interne: 0 cm; Décalage séparation: 0 cm; Appui extérieur: 0 cm; Appui intérieur: 0 cm; Côté latéral externe: 0 cm; Côté latéral interne: 0 cm
IFC_Pset_Géométrie_Chambranle - Position: Aucun; Épaisseur Chambranle intérieur: 0 cm; Longueur Chambranle intérieur: 0 cm; Superposition Chambranle intérieur: 0 cm; Épaisseur Intrados: 0 cm; Épaisseur Chambranle extérieur: 0 cm; Largeur Chambranle extérieur: 0 cm; Superposition Chambranle extérieur: 0 cm; Épaisseur Intrados extérieur: 0 cm
IFC_Pset_Géométrie_CORNICHE depuis profil - Position: Aucune; sets with these values: 2
IFC_Pset_Géométrie_CORNICHE Extérieure à partir d'un profil - Décalage: 0; Angle: 0 deg; Symétrie: no; Fermer: no; sets with these values: 2
IFC_Pset_Géométrie_BASE Extérieure à partir d'un profil - Angle: 0 deg; Symétrie: no; Côté: 0 cm; sets with these values: 2
IFC_Pset_Géométrie_1° MENUISERIE - Position: Extérieur; Décalage: 0 cm
IFC_Pset_Géométrie_2° MENUISERIE - Décalage: 0 cm
IFC_Pset_Géométrie - Côté extérieur: 0; Invertir (dte/gche): yes; Invertir (intérieur/extérieur): yes; Largeur: 93.7891 cm; Hauteur: 205 cm; Hauteur 2: 0 cm; Rayon Arc: 0 cm; Rayon Cercle: 0 cm; Demi-axe horizontal: 0 cm; Demi-axe vertical: 0 cm
IFC_Pset_Géométrie_GRILLE - décalage: 0 cm; Offset latéral: 0 cm; Décalage supérieur: 0 cm; Décalage inférieur: 0 cm; Nombre accrochages latéraux: 0; Nombre d'accrochages supérieurs: 0; Nombre accrochages inférieurs: 0
IFC_Pset_Système de Référence Altimétrique_INFÉRIEUR - NIVEAU: Rez-de-Jardin (Rez-de-Jardin 15545); delta: 2.51092 cm; sous Niveau: <aucun>
IFC_Pset_Données Métré - Surface 1re Menuiserie: 19200 cm2; Surface Vitre 1re Menuiserie: 13200 cm2; Surface du Cadre de la 1re Menuiserie: 3700 cm2; Surface 2e Menuiserie: 0 cm2; Surface Vitre 2e Menuiserie: 0 cm2; Surface du Cadre de la 2ème Menuiserie: 0 cm2; Surface de l'Ouverture: 19200 cm2; Surface de l'Ébrasement: 0 cm2; Surface du Seuil: 0 cm2; Surface du Seuil intérieur: 0 cm2; Volume du seuil: 0 cm3; Volume du seuil intérieur: 0 cm3; Surface de la Grille: 0 cm2; Volume de la Grille: 0 cm3
IFC_Pset_Matériaux_1° MENUISERIE - Cadre externe: Vert clair_porte; Verre: Transparent; Panneau extérieur: Vert clair_porte; Poignée: Aluminium satiné
Pset_DoorCommon - Reference: Porte_1VB[2P] (..\Porte moderne\1 Vantail Battant\) <aucun>

# IfcDoor: Porte_1VB[2P]_IMP verre, Porte 78732
In: Rez-de-Jardin
Type - ParameterTakesPrecedence: no; Sizeable: no; Material: Transparent, Aluminium satiné, Blanc trafic
Type - IfcDoorLiningProperties - LiningDepth: 8 cm; LiningThickness: 3 cm
Description: Porte; OverallHeight: 252 cm; OverallWidth: 90 cm
__RECOGNIZE__ - ID: 78732; TPLG: 102; TPLG_OD: 9005; GENERATE: 1
CTLG_EXTERNAL_LINK - 0, DocType: 3; 0, Tag: 100; 0, Crc: 379042420; 1, DocType: 2; 1, Tag: 0; 1, Crc: -746779066; 2, DocType: 2; 2, Tag: 102; 2, Crc: -848491367; 3, DocType: 2; 3, Tag: 104; 3, Crc: -623492449; 4, DocType: 2; 4, Tag: 105; 4, Crc: -848491367; 5, DocType: 2; 5, Tag: 107; 5, Crc: 1305662025
IFC_PSET_PolygonOffset - polygonOffsetFactor: 2; polygonOffsetUnits: 2
IFC_Pset_Caractéristiques - ID: 78732; Numérotation: 38; Numéro niveau: 02; Titre niveau: Rez-de-Jardin; Modèle 1re menuiserie: Porte_1VB[2P]_IMP verre
IFC_Pset_Géométrie_Ébrasement - Présent: no; Côté supérieur: no; Côté INFÉRIEUR: no; Épaisseur extérieure: 0 cm; Épaisseur latérale gauche: 0 cm; Épaisseur latérale droite: 0 cm; Épiasseur latérale supérieure: 0 cm; Épaisseur diagonale gauche: 0 cm; Épaisseur diagonale droite: 0 cm; Épaisseur diagonale inférieure: 0 cm; Épaisseur diagonale supérieure: 0 cm; Épaisseur intérieur: 0 cm
IFC_Pset_Géométrie_Seuil - Type: Aucun; Épaisseur: 0 cm; Épaisseur interne: 0 cm; Décalage séparation: 0 cm; Appui extérieur: 0 cm; Appui intérieur: 0 cm; Côté latéral externe: 0 cm; Côté latéral interne: 0 cm
IFC_Pset_Géométrie_Chambranle - Position: Aucun; Épaisseur Chambranle intérieur: 0 cm; Longueur Chambranle intérieur: 0 cm; Superposition Chambranle intérieur: 0 cm; Épaisseur Intrados: 0 cm; Épaisseur Chambranle extérieur: 0 cm; Largeur Chambranle extérieur: 0 cm; Superposition Chambranle extérieur: 0 cm; Épaisseur Intrados extérieur: 0 cm
IFC_Pset_Géométrie_CORNICHE depuis profil - Position: Aucune; sets with these values: 2
IFC_Pset_Géométrie_CORNICHE Extérieure à partir d'un profil - Décalage: 0; Angle: 0 deg; Symétrie: no; Fermer: no; sets with these values: 2
IFC_Pset_Géométrie_BASE Extérieure à partir d'un profil - Angle: 0 deg; Symétrie: no; Côté: 0 cm; sets with these values: 2
IFC_Pset_Géométrie_1° MENUISERIE - Position: Intérieur; Décalage: 0 cm
IFC_Pset_Géométrie_2° MENUISERIE - Décalage: 0 cm
IFC_Pset_Géométrie - Côté extérieur: 1; Invertir (dte/gche): no; Invertir (intérieur/extérieur): yes; Largeur: 90 cm; Hauteur: 252 cm; Hauteur 2: 0 cm; Rayon Arc: 0 cm; Rayon Cercle: 0 cm; Demi-axe horizontal: 0 cm; Demi-axe vertical: 0 cm
IFC_Pset_Géométrie_GRILLE - décalage: 0 cm; Offset latéral: 0 cm; Décalage supérieur: 0 cm; Décalage inférieur: 0 cm; Nombre accrochages latéraux: 0; Nombre d'accrochages supérieurs: 0; Nombre accrochages inférieurs: 0
IFC_Pset_Système de Référence Altimétrique_INFÉRIEUR - NIVEAU: Rez-de-Jardin (Rez-de-Jardin 15545); delta: 0.601515 cm; sous Niveau: <aucun>
IFC_Pset_Données Métré - Surface 1re Menuiserie: 22700 cm2; Surface Vitre 1re Menuiserie: 11900 cm2; Surface du Cadre de la 1re Menuiserie: 9500 cm2; Surface 2e Menuiserie: 0 cm2; Surface Vitre 2e Menuiserie: 0 cm2; Surface du Cadre de la 2ème Menuiserie: 0 cm2; Surface de l'Ouverture: 22700 cm2; Surface de l'Ébrasement: 0 cm2; Surface du Seuil: 0 cm2; Surface du Seuil intérieur: 0 cm2; Volume du seuil: 0 cm3; Volume du seuil intérieur: 0 cm3; Surface de la Grille: 0 cm2; Volume de la Grille: 0 cm3
IFC_Pset_Matériaux_1° MENUISERIE - Cadre externe: Blanc trafic; Verre: Transparent; Panneau extérieur: Blanc trafic; Poignée: Aluminium satiné
Pset_DoorCommon - Reference: Porte_1VB[2P]_IMP verre (..\Porte moderne\1 Vantail Battant\) <aucun>

# IfcDoor: Porte_2VB[1P verre]_IMP verre_2P verre-extérieur 2, Porte 15527
In: Rez-de-chaussée
Type - OperationType: DOUBLE_DOOR_SINGLE_SWING; ParameterTakesPrecedence: no; Sizeable: no; Material: Transparent, Aluminium satiné, Blanc trafic
Type - IfcDoorLiningProperties - LiningDepth: 8 cm; LiningThickness: 3 cm
Description: Porte; OverallHeight: 304.504 cm; OverallWidth: 329.047 cm
__RECOGNIZE__ - ID: 15527; TPLG: 102; TPLG_OD: 9005; GENERATE: 1
CTLG_EXTERNAL_LINK - 0, DocType: 3; 0, Tag: 100; 0, Crc: -626436760; 1, DocType: 2; 1, Tag: 0; 1, Crc: -746779066; 2, DocType: 2; 2, Tag: 102; 2, Crc: -848491367; 3, DocType: 2; 3, Tag: 104; 3, Crc: -623492449; 4, DocType: 2; 4, Tag: 107; 4, Crc: 1305662025
IFC_PSET_PolygonOffset - polygonOffsetFactor: 2; polygonOffsetUnits: 2
IFC_Pset_Caractéristiques - ID: 15527; Numérotation: 01; Numéro niveau: 03; Titre niveau: Rez-de-chaussée; Modèle 1re menuiserie: Porte_2VB[1P verre]_IMP verre_2P verre-extérieur 2
IFC_Pset_Géométrie_Ébrasement - Présent: yes; Côté supérieur: no; Côté INFÉRIEUR: no; Épaisseur extérieure: 8 cm; Épaisseur latérale gauche: 0 cm; Épaisseur latérale droite: 0 cm; Épiasseur latérale supérieure: 0 cm; Épaisseur diagonale gauche: 3 cm; Épaisseur diagonale droite: 4.5 cm; Épaisseur diagonale inférieure: 3 cm; Épaisseur diagonale supérieure: 3 cm; Épaisseur intérieur: 0 cm; Données: [a : 80,00; b: 0,00; c: 30,00; d: 0,00] mm
IFC_Pset_Géométrie_Seuil - Type: Aucun; Épaisseur: 0 cm; Épaisseur interne: 0 cm; Décalage séparation: 0 cm; Appui extérieur: 0 cm; Appui intérieur: 0 cm; Côté latéral externe: 0 cm; Côté latéral interne: 0 cm
IFC_Pset_Géométrie_Chambranle - Position: Aucun; Épaisseur Chambranle intérieur: 0 cm; Longueur Chambranle intérieur: 0 cm; Superposition Chambranle intérieur: 0 cm; Épaisseur Intrados: 0 cm; Épaisseur Chambranle extérieur: 0 cm; Largeur Chambranle extérieur: 0 cm; Superposition Chambranle extérieur: 0 cm; Épaisseur Intrados extérieur: 0 cm
IFC_Pset_Géométrie_CORNICHE depuis profil - Position: Aucune; sets with these values: 2
IFC_Pset_Géométrie_CORNICHE Extérieure à partir d'un profil - Décalage: 0; Angle: 0 deg; Symétrie: no; Fermer: no; sets with these values: 2
IFC_Pset_Géométrie_BASE Extérieure à partir d'un profil - Angle: 0 deg; Symétrie: no; Côté: 0 cm; sets with these values: 2
IFC_Pset_Géométrie_1° MENUISERIE - Position: Extérieur; Décalage: -1 cm
IFC_Pset_Géométrie_2° MENUISERIE - Décalage: 0 cm
IFC_Pset_Géométrie - Côté extérieur: 1; Invertir (dte/gche): no; Invertir (intérieur/extérieur): no; Largeur: 329.047 cm; Hauteur: 304.504 cm; Hauteur 2: 0 cm; Rayon Arc: 0 cm; Rayon Cercle: 0 cm; Demi-axe horizontal: 0 cm; Demi-axe vertical: 0 cm
IFC_Pset_Géométrie_GRILLE - décalage: 0 cm; Offset latéral: 0 cm; Décalage supérieur: 0 cm; Décalage inférieur: 0 cm; Nombre accrochages latéraux: 0; Nombre d'accrochages supérieurs: 0; Nombre accrochages inférieurs: 0
IFC_Pset_Système de Référence Altimétrique_INFÉRIEUR - NIVEAU: Rez-de-chaussée (Rez-de-chaussée 1047); delta: 0.0128504 cm; sous Niveau: <aucun>
IFC_Pset_Données Métré - Surface 1re Menuiserie: 100200 cm2; Surface Vitre 1re Menuiserie: 78500 cm2; Surface du Cadre de la 1re Menuiserie: 21700 cm2; Surface 2e Menuiserie: 0 cm2; Surface Vitre 2e Menuiserie: 0 cm2; Surface du Cadre de la 2ème Menuiserie: 0 cm2; Surface de l'Ouverture: 100200 cm2; Surface de l'Ébrasement: 23000 cm2; Surface du Seuil: 0 cm2; Surface du Seuil intérieur: 0 cm2; Volume du seuil: 0 cm3; Volume du seuil intérieur: 0 cm3; Surface de la Grille: 0 cm2; Volume de la Grille: 0 cm3
IFC_Pset_Matériaux_1° MENUISERIE - Cadre externe: Blanc trafic; Verre: Transparent; Poignée: Aluminium satiné
Pset_DoorCommon - Reference: Porte_2VB[1P verre]_IMP verre_2P verre-extérieur 2 (..\Porte moderne\2 Vantaux Battants\) <aucun>

# IfcDoor: Porte_2VB[1P] (3)
Type - OperationType: DOUBLE_DOOR_SINGLE_SWING; ParameterTakesPrecedence: yes; Sizeable: no; Material: Aluminium satiné, Blanc trafic
Type - IfcDoorLiningProperties - LiningDepth: 8 cm; LiningThickness: 3 cm
Type - IfcDoorPanelProperties - PanelDepth: 4 cm; PanelOperation: SWINGING; PanelWidth: 0.5; PanelPosition: LEFT
Description: Porte
__RECOGNIZE__ - TPLG: 102; TPLG_OD: 9005; GENERATE: 1
CTLG_EXTERNAL_LINK - 0, DocType: 3; 0, Tag: 100; 0, Crc: -575706680; 1, DocType: 2; 1, Tag: 0; 1, Crc: -746779066; 2, DocType: 2; 2, Tag: 102; 2, Crc: -848491367; 3, DocType: 2; 3, Tag: 105; 3, Crc: -848491367; 4, DocType: 2; 4, Tag: 107; 4, Crc: 1305662025
IFC_PSET_PolygonOffset - polygonOffsetFactor: 2; polygonOffsetUnits: 2
IFC_Pset_Caractéristiques - Modèle 1re menuiserie: Porte_2VB[1P]
IFC_Pset_Géométrie_Ébrasement - Présent: no; Côté supérieur: no; Côté INFÉRIEUR: no; Épaisseur extérieure: 0 cm; Épaisseur latérale gauche: 0 cm; Épaisseur latérale droite: 0 cm; Épiasseur latérale supérieure: 0 cm; Épaisseur diagonale gauche: 0 cm; Épaisseur diagonale droite: 0 cm; Épaisseur diagonale inférieure: 0 cm; Épaisseur diagonale supérieure: 0 cm; Épaisseur intérieur: 0 cm
IFC_Pset_Géométrie_Seuil - Type: Aucun; Épaisseur: 0 cm; Épaisseur interne: 0 cm; Décalage séparation: 0 cm; Appui extérieur: 0 cm; Appui intérieur: 0 cm; Côté latéral externe: 0 cm; Côté latéral interne: 0 cm
IFC_Pset_Géométrie_Chambranle - Position: Aucun; Épaisseur Chambranle intérieur: 0 cm; Longueur Chambranle intérieur: 0 cm; Superposition Chambranle intérieur: 0 cm; Épaisseur Intrados: 0 cm; Épaisseur Chambranle extérieur: 0 cm; Largeur Chambranle extérieur: 0 cm; Superposition Chambranle extérieur: 0 cm; Épaisseur Intrados extérieur: 0 cm
IFC_Pset_Géométrie_CORNICHE depuis profil - Position: Aucune; sets with these values: 2
IFC_Pset_Géométrie_CORNICHE Extérieure à partir d'un profil - Décalage: 0; Angle: 0 deg; Symétrie: no; Fermer: no; sets with these values: 2
IFC_Pset_Géométrie_BASE Extérieure à partir d'un profil - Angle: 0 deg; Symétrie: no; Côté: 0 cm; sets with these values: 2
IFC_Pset_Géométrie_1° MENUISERIE - Position: Extérieur; Décalage: 0 cm
IFC_Pset_Géométrie_2° MENUISERIE - Décalage: 0 cm
IFC_Pset_Géométrie - Hauteur 2: 0 cm; Rayon Arc: 0 cm; Rayon Cercle: 0 cm; Demi-axe horizontal: 0 cm; Demi-axe vertical: 0 cm
IFC_Pset_Géométrie_GRILLE - décalage: 0 cm; Offset latéral: 0 cm; Décalage supérieur: 0 cm; Décalage inférieur: 0 cm; Nombre accrochages latéraux: 0; Nombre d'accrochages supérieurs: 0; Nombre accrochages inférieurs: 0
IFC_Pset_Système de Référence Altimétrique_INFÉRIEUR - sous Niveau: <aucun>
IFC_Pset_Données Métré - Surface Vitre 1re Menuiserie: 0 cm2; Surface 2e Menuiserie: 0 cm2; Surface Vitre 2e Menuiserie: 0 cm2; Surface du Cadre de la 2ème Menuiserie: 0 cm2; Surface de l'Ébrasement: 0 cm2; Surface du Seuil: 0 cm2; Surface du Seuil intérieur: 0 cm2; Volume du seuil: 0 cm3; Volume du seuil intérieur: 0 cm3; Surface de la Grille: 0 cm2; Volume de la Grille: 0 cm3
IFC_Pset_Matériaux_1° MENUISERIE - Cadre externe: Blanc trafic; Panneau extérieur: Blanc trafic; Poignée: Aluminium satiné
Pset_DoorCommon - Reference: Porte_2VB[1P] (..\Porte moderne\2 Vantaux Battants\) <aucun>
Name | In | OverallHeight (cm) = Hauteur (cm) | OverallWidth (cm) = Largeur (cm) | __RECOGNIZE__, ID = IFC_Pset_Caractéristiques, ID | Numérotation | Numéro niveau | Titre niveau | Côté extérieur | Invertir (dte/gche) | Invertir (intérieur/extérieur) | NIVEAU | delta (cm) | Surface 1re Menuiserie (cm2) = Surface de l'Ouverture (cm2) | Surface du Cadre de la 1re Menuiserie (cm2)
Porte 73927 | Rez-de-Jardin | 203 | 158 | 73927 | 22 | 02 | Rez-de-Jardin | 0 | no | yes | Rez-de-Jardin (Rez-de-Jardin 15545) | 2.51092 | 32100 | 1700
Porte 120669 | Niveau 1 | 207 | 106.302 | 120669 | 57 | 04 | Niveau 1 | 0 | no | no | Niveau 1 (Niveau 1 2343) | 0.0128504 | 22000 | 1500
Porte 170541 | Niveau 2 | 205 | 92.1432 | 170541 | 75 | 05 | Niveau 2 | 1 | yes | yes | Niveau 2 (Niveau 2 13545) | 1.24345e-12 | 18900 | 1500

# IfcDoor: Porte_2VB[1P], Porte 74078
In: Rez-de-Jardin
Type - OperationType: DOUBLE_DOOR_SINGLE_SWING; ParameterTakesPrecedence: yes; Sizeable: no; Material: Aluminium satiné, Rouge brillant, Blanc trafic
Type - IfcDoorLiningProperties - LiningDepth: 8 cm; LiningThickness: 3 cm
Type - IfcDoorPanelProperties - PanelDepth: 4 cm; PanelOperation: SWINGING; PanelWidth: 0.5; PanelPosition: LEFT
Description: Porte; OverallHeight: 109 cm; OverallWidth: 110.665 cm
__RECOGNIZE__ - ID: 74078; TPLG: 102; TPLG_OD: 9005; GENERATE: 1
CTLG_EXTERNAL_LINK - 0, DocType: 3; 0, Tag: 100; 0, Crc: -575706680; 1, DocType: 2; 1, Tag: 0; 1, Crc: -746779066; 2, DocType: 2; 2, Tag: 102; 2, Crc: -848491367; 3, DocType: 2; 3, Tag: 105; 3, Crc: 1680698050; 4, DocType: 2; 4, Tag: 107; 4, Crc: 1305662025
IFC_PSET_PolygonOffset - polygonOffsetFactor: 2; polygonOffsetUnits: 2
IFC_Pset_Caractéristiques - ID: 74078; Numérotation: 25; Numéro niveau: 02; Titre niveau: Rez-de-Jardin; Modèle 1re menuiserie: Porte_2VB[1P]
IFC_Pset_Géométrie_Ébrasement - Présent: no; Côté supérieur: no; Côté INFÉRIEUR: no; Épaisseur extérieure: 0 cm; Épaisseur latérale gauche: 0 cm; Épaisseur latérale droite: 0 cm; Épiasseur latérale supérieure: 0 cm; Épaisseur diagonale gauche: 0 cm; Épaisseur diagonale droite: 0 cm; Épaisseur diagonale inférieure: 0 cm; Épaisseur diagonale supérieure: 0 cm; Épaisseur intérieur: 0 cm
IFC_Pset_Géométrie_Seuil - Type: Aucun; Épaisseur: 0 cm; Épaisseur interne: 0 cm; Décalage séparation: 0 cm; Appui extérieur: 0 cm; Appui intérieur: 0 cm; Côté latéral externe: 0 cm; Côté latéral interne: 0 cm
IFC_Pset_Géométrie_Chambranle - Position: Aucun; Épaisseur Chambranle intérieur: 0 cm; Longueur Chambranle intérieur: 0 cm; Superposition Chambranle intérieur: 0 cm; Épaisseur Intrados: 0 cm; Épaisseur Chambranle extérieur: 0 cm; Largeur Chambranle extérieur: 0 cm; Superposition Chambranle extérieur: 0 cm; Épaisseur Intrados extérieur: 0 cm
IFC_Pset_Géométrie_CORNICHE depuis profil - Position: Aucune; sets with these values: 2
IFC_Pset_Géométrie_CORNICHE Extérieure à partir d'un profil - Décalage: 0; Angle: 0 deg; Symétrie: no; Fermer: no; sets with these values: 2
IFC_Pset_Géométrie_BASE Extérieure à partir d'un profil - Angle: 0 deg; Symétrie: no; Côté: 0 cm; sets with these values: 2
IFC_Pset_Géométrie_1° MENUISERIE - Position: Centre; Décalage: 0 cm
IFC_Pset_Géométrie_2° MENUISERIE - Décalage: 0 cm
IFC_Pset_Géométrie - Côté extérieur: 1; Invertir (dte/gche): no; Invertir (intérieur/extérieur): no; Largeur: 110.665 cm; Hauteur: 109 cm; Hauteur 2: 0 cm; Rayon Arc: 0 cm; Rayon Cercle: 0 cm; Demi-axe horizontal: 0 cm; Demi-axe vertical: 0 cm
IFC_Pset_Géométrie_GRILLE - décalage: 0 cm; Offset latéral: 0 cm; Décalage supérieur: 0 cm; Décalage inférieur: 0 cm; Nombre accrochages latéraux: 0; Nombre d'accrochages supérieurs: 0; Nombre accrochages inférieurs: 0
IFC_Pset_Système de Référence Altimétrique_INFÉRIEUR - NIVEAU: Rez-de-Jardin (Rez-de-Jardin 15545); delta: 115.706 cm; sous Niveau: <aucun>
IFC_Pset_Données Métré - Surface 1re Menuiserie: 12100 cm2; Surface Vitre 1re Menuiserie: 0 cm2; Surface du Cadre de la 1re Menuiserie: 1000 cm2; Surface 2e Menuiserie: 0 cm2; Surface Vitre 2e Menuiserie: 0 cm2; Surface du Cadre de la 2ème Menuiserie: 0 cm2; Surface de l'Ouverture: 12100 cm2; Surface de l'Ébrasement: 0 cm2; Surface du Seuil: 0 cm2; Surface du Seuil intérieur: 0 cm2; Volume du seuil: 0 cm3; Volume du seuil intérieur: 0 cm3; Surface de la Grille: 0 cm2; Volume de la Grille: 0 cm3
IFC_Pset_Matériaux_1° MENUISERIE - Cadre externe: Blanc trafic; Panneau extérieur: Rouge brillant; Poignée: Aluminium satiné
Pset_DoorCommon - Reference: Porte_2VB[1P] (..\Porte moderne\2 Vantaux Battants\) <aucun>

# IfcDoor: Porte_2VB[1P] (6)
In: Mezzanine
Type - OperationType: DOUBLE_DOOR_SINGLE_SWING; ParameterTakesPrecedence: yes; Sizeable: no; Material: Aluminium satiné, Violet pastel
Type - IfcDoorLiningProperties - LiningDepth: 8 cm; LiningThickness: 3 cm
Type - IfcDoorPanelProperties - PanelDepth: 4 cm; PanelOperation: SWINGING; PanelWidth: 0.5; PanelPosition: LEFT
Description: Porte
__RECOGNIZE__ - TPLG: 102; TPLG_OD: 9005; GENERATE: 1
CTLG_EXTERNAL_LINK - 0, DocType: 3; 0, Tag: 100; 0, Crc: -575706680; 1, DocType: 2; 1, Tag: 0; 1, Crc: -746779066; 2, DocType: 2; 2, Tag: 102; 2, Crc: 1670416681; 3, DocType: 2; 3, Tag: 105; 3, Crc: 1670416681; 4, DocType: 2; 4, Tag: 107; 4, Crc: 1305662025
IFC_PSET_PolygonOffset - polygonOffsetFactor: 2; polygonOffsetUnits: 2
IFC_Pset_Caractéristiques - Numéro niveau: 06; Titre niveau: Mezzanine; Modèle 1re menuiserie: Porte_2VB[1P]
IFC_Pset_Géométrie_Ébrasement - Présent: no; Côté supérieur: no; Côté INFÉRIEUR: no; Épaisseur extérieure: 0 cm; Épaisseur latérale gauche: 0 cm; Épaisseur latérale droite: 0 cm; Épiasseur latérale supérieure: 0 cm; Épaisseur diagonale gauche: 0 cm; Épaisseur diagonale droite: 0 cm; Épaisseur diagonale inférieure: 0 cm; Épaisseur diagonale supérieure: 0 cm; Épaisseur intérieur: 0 cm
IFC_Pset_Géométrie_Seuil - Type: Aucun; Épaisseur: 0 cm; Épaisseur interne: 0 cm; Décalage séparation: 0 cm; Appui extérieur: 0 cm; Appui intérieur: 0 cm; Côté latéral externe: 0 cm; Côté latéral interne: 0 cm
IFC_Pset_Géométrie_Chambranle - Position: Aucun; Épaisseur Chambranle intérieur: 0 cm; Longueur Chambranle intérieur: 0 cm; Superposition Chambranle intérieur: 0 cm; Épaisseur Intrados: 0 cm; Épaisseur Chambranle extérieur: 0 cm; Largeur Chambranle extérieur: 0 cm; Superposition Chambranle extérieur: 0 cm; Épaisseur Intrados extérieur: 0 cm
IFC_Pset_Géométrie_CORNICHE depuis profil - Position: Aucune; sets with these values: 2
IFC_Pset_Géométrie_CORNICHE Extérieure à partir d'un profil - Décalage: 0; Angle: 0 deg; Symétrie: no; Fermer: no; sets with these values: 2
IFC_Pset_Géométrie_BASE Extérieure à partir d'un profil - Angle: 0 deg; Symétrie: no; Côté: 0 cm; sets with these values: 2
IFC_Pset_Géométrie_1° MENUISERIE - Position: Extérieur; Décalage: 0 cm
IFC_Pset_Géométrie_2° MENUISERIE - Décalage: 0 cm
IFC_Pset_Géométrie - Côté extérieur: 1; Invertir (dte/gche): yes; Invertir (intérieur/extérieur): yes; Hauteur 2: 0 cm; Rayon Arc: 0 cm; Rayon Cercle: 0 cm; Demi-axe horizontal: 0 cm; Demi-axe vertical: 0 cm
IFC_Pset_Géométrie_GRILLE - décalage: 0 cm; Offset latéral: 0 cm; Décalage supérieur: 0 cm; Décalage inférieur: 0 cm; Nombre accrochages latéraux: 0; Nombre d'accrochages supérieurs: 0; Nombre accrochages inférieurs: 0
IFC_Pset_Système de Référence Altimétrique_INFÉRIEUR - NIVEAU: Mezzanine (Mezzanine 49003); sous Niveau: <aucun>
IFC_Pset_Données Métré - Surface Vitre 1re Menuiserie: 0 cm2; Surface 2e Menuiserie: 0 cm2; Surface Vitre 2e Menuiserie: 0 cm2; Surface du Cadre de la 2ème Menuiserie: 0 cm2; Surface de l'Ébrasement: 0 cm2; Surface du Seuil: 0 cm2; Surface du Seuil intérieur: 0 cm2; Volume du seuil: 0 cm3; Volume du seuil intérieur: 0 cm3; Surface de la Grille: 0 cm2; Volume de la Grille: 0 cm3
IFC_Pset_Matériaux_1° MENUISERIE - Cadre externe: Violet pastel; Panneau extérieur: Violet pastel; Poignée: Aluminium satiné
Pset_DoorCommon - Reference: Porte_2VB[1P] (..\Porte moderne\2 Vantaux Battants\) <aucun>
Name | OverallHeight (cm) = Hauteur (cm) | OverallWidth (cm) = Largeur (cm) | __RECOGNIZE__, ID = IFC_Pset_Caractéristiques, ID | Numérotation | delta (cm) | Surface 1re Menuiserie (cm2) = Surface de l'Ouverture (cm2) | Surface du Cadre de la 1re Menuiserie (cm2)
Porte 198489 | 99.5059 | 90 | 198489 | 84 | 138 | 9000 | 800
Porte 198484 | 70 | 100 | 198484 | 82 | 58 | 7000 | 700
Porte 198488 | 70 | 90 | 198488 | 83 | 58 | 6300 | 700
Porte 198483 | 99.5059 | 100 | 198483 | 81 | 138 | 10000 | 900
Porte 198481 | 70 | 100 | 198481 | 79 | 58 | 7000 | 700
Porte 198482 | 99.5059 | 100 | 198482 | 80 | 138 | 10000 | 900

# IfcDoor: Porte_2VB[1P] (4)
In: Niveau 1
Type - OperationType: DOUBLE_DOOR_SINGLE_SWING; ParameterTakesPrecedence: yes; Sizeable: no; Material: Blanc gris, Aluminium satiné, Blanc trafic
Type - IfcDoorLiningProperties - LiningDepth: 8 cm; LiningThickness: 3 cm
Type - IfcDoorPanelProperties - PanelDepth: 4 cm; PanelOperation: SWINGING; PanelWidth: 0.5; PanelPosition: LEFT
Description: Porte
__RECOGNIZE__ - TPLG: 102; TPLG_OD: 9005; GENERATE: 1
CTLG_EXTERNAL_LINK - 0, DocType: 3; 0, Tag: 100; 0, Crc: -575706680; 1, DocType: 2; 1, Tag: 0; 1, Crc: -746779066; 2, DocType: 2; 2, Tag: 102; 2, Crc: 2064387956; 3, DocType: 2; 3, Tag: 105; 3, Crc: -848491367; 4, DocType: 2; 4, Tag: 107; 4, Crc: 1305662025
IFC_PSET_PolygonOffset - polygonOffsetFactor: 2; polygonOffsetUnits: 2
IFC_Pset_Caractéristiques - Numéro niveau: 04; Titre niveau: Niveau 1; Modèle 1re menuiserie: Porte_2VB[1P]
IFC_Pset_Géométrie_Ébrasement - Présent: no; Côté supérieur: no; Côté INFÉRIEUR: no; Épaisseur extérieure: 0 cm; Épaisseur latérale gauche: 0 cm; Épaisseur latérale droite: 0 cm; Épiasseur latérale supérieure: 0 cm; Épaisseur diagonale gauche: 0 cm; Épaisseur diagonale droite: 0 cm; Épaisseur diagonale inférieure: 0 cm; Épaisseur diagonale supérieure: 0 cm; Épaisseur intérieur: 0 cm
IFC_Pset_Géométrie_Seuil - Type: Aucun; Épaisseur: 0 cm; Épaisseur interne: 0 cm; Décalage séparation: 0 cm; Appui extérieur: 0 cm; Appui intérieur: 0 cm; Côté latéral externe: 0 cm; Côté latéral interne: 0 cm
IFC_Pset_Géométrie_Chambranle - Position: Aucun; Épaisseur Chambranle intérieur: 0 cm; Longueur Chambranle intérieur: 0 cm; Superposition Chambranle intérieur: 0 cm; Épaisseur Intrados: 0 cm; Épaisseur Chambranle extérieur: 0 cm; Largeur Chambranle extérieur: 0 cm; Superposition Chambranle extérieur: 0 cm; Épaisseur Intrados extérieur: 0 cm
IFC_Pset_Géométrie_CORNICHE depuis profil - Position: Aucune; sets with these values: 2
IFC_Pset_Géométrie_CORNICHE Extérieure à partir d'un profil - Décalage: 0; Angle: 0 deg; Symétrie: no; Fermer: no; sets with these values: 2
IFC_Pset_Géométrie_BASE Extérieure à partir d'un profil - Angle: 0 deg; Symétrie: no; Côté: 0 cm; sets with these values: 2
IFC_Pset_Géométrie_1° MENUISERIE - Position: Extérieur; Décalage: 0 cm
IFC_Pset_Géométrie_2° MENUISERIE - Décalage: 0 cm
IFC_Pset_Géométrie - Côté extérieur: 0; Invertir (dte/gche): no; Invertir (intérieur/extérieur): yes; Hauteur 2: 0 cm; Rayon Arc: 0 cm; Rayon Cercle: 0 cm; Demi-axe horizontal: 0 cm; Demi-axe vertical: 0 cm
IFC_Pset_Géométrie_GRILLE - décalage: 0 cm; Offset latéral: 0 cm; Décalage supérieur: 0 cm; Décalage inférieur: 0 cm; Nombre accrochages latéraux: 0; Nombre d'accrochages supérieurs: 0; Nombre accrochages inférieurs: 0
IFC_Pset_Système de Référence Altimétrique_INFÉRIEUR - NIVEAU: Niveau 1 (Niveau 1 2343); delta: 0.0128504 cm; sous Niveau: <aucun>
IFC_Pset_Données Métré - Surface Vitre 1re Menuiserie: 0 cm2; Surface du Cadre de la 1re Menuiserie: 1600 cm2; Surface 2e Menuiserie: 0 cm2; Surface Vitre 2e Menuiserie: 0 cm2; Surface du Cadre de la 2ème Menuiserie: 0 cm2; Surface de l'Ébrasement: 0 cm2; Surface du Seuil: 0 cm2; Surface du Seuil intérieur: 0 cm2; Volume du seuil: 0 cm3; Volume du seuil intérieur: 0 cm3; Surface de la Grille: 0 cm2; Volume de la Grille: 0 cm3
IFC_Pset_Matériaux_1° MENUISERIE - Cadre externe: Blanc gris; Panneau extérieur: Blanc trafic; Poignée: Aluminium satiné
Pset_DoorCommon - Reference: Porte_2VB[1P] (..\Porte moderne\2 Vantaux Battants\) <aucun>
Name | OverallHeight (cm) = Hauteur (cm) | OverallWidth (cm) = Largeur (cm) | __RECOGNIZE__, ID = IFC_Pset_Caractéristiques, ID | Numérotation | Surface 1re Menuiserie (cm2) = Surface de l'Ouverture (cm2)
Porte 104274 | 203.1 | 126.516 | 104274 | 52 | 25700
Porte 104273 | 203.1 | 130 | 104273 | 51 | 26400
Porte 104271 | 202.4 | 126.804 | 104271 | 49 | 25700
Porte 104272 | 202.4 | 128.215 | 104272 | 50 | 26000

# IfcDoor: Porte_2VB[1P], Porte 121247
In: Niveau 1
Type - OperationType: DOUBLE_DOOR_SINGLE_SWING; ParameterTakesPrecedence: yes; Sizeable: no; Material: Gris de sécurité, Aluminium satiné
Type - IfcDoorLiningProperties - LiningDepth: 8 cm; LiningThickness: 3 cm
Type - IfcDoorPanelProperties - PanelDepth: 4 cm; PanelOperation: SWINGING; PanelWidth: 0.5; PanelPosition: LEFT
Description: Porte; OverallHeight: 208 cm; OverallWidth: 108.814 cm
__RECOGNIZE__ - ID: 121247; TPLG: 102; TPLG_OD: 9005; GENERATE: 1
CTLG_EXTERNAL_LINK - 0, DocType: 3; 0, Tag: 100; 0, Crc: -575706680; 1, DocType: 2; 1, Tag: 0; 1, Crc: -746779066; 2, DocType: 2; 2, Tag: 102; 2, Crc: -205025647; 3, DocType: 2; 3, Tag: 105; 3, Crc: -205025647; 4, DocType: 2; 4, Tag: 107; 4, Crc: 1305662025
IFC_PSET_PolygonOffset - polygonOffsetFactor: 2; polygonOffsetUnits: 2
IFC_Pset_Caractéristiques - ID: 121247; Numérotation: 60; Numéro niveau: 04; Titre niveau: Niveau 1; Modèle 1re menuiserie: Porte_2VB[1P]
IFC_Pset_Géométrie_Ébrasement - Présent: no; Côté supérieur: no; Côté INFÉRIEUR: no; Épaisseur extérieure: 0 cm; Épaisseur latérale gauche: 0 cm; Épaisseur latérale droite: 0 cm; Épiasseur latérale supérieure: 0 cm; Épaisseur diagonale gauche: 0 cm; Épaisseur diagonale droite: 0 cm; Épaisseur diagonale inférieure: 0 cm; Épaisseur diagonale supérieure: 0 cm; Épaisseur intérieur: 0 cm
IFC_Pset_Géométrie_Seuil - Type: Aucun; Épaisseur: 0 cm; Épaisseur interne: 0 cm; Décalage séparation: 0 cm; Appui extérieur: 0 cm; Appui intérieur: 0 cm; Côté latéral externe: 0 cm; Côté latéral interne: 0 cm
IFC_Pset_Géométrie_Chambranle - Position: Aucun; Épaisseur Chambranle intérieur: 0 cm; Longueur Chambranle intérieur: 0 cm; Superposition Chambranle intérieur: 0 cm; Épaisseur Intrados: 0 cm; Épaisseur Chambranle extérieur: 0 cm; Largeur Chambranle extérieur: 0 cm; Superposition Chambranle extérieur: 0 cm; Épaisseur Intrados extérieur: 0 cm
IFC_Pset_Géométrie_CORNICHE depuis profil - Position: Aucune; sets with these values: 2
IFC_Pset_Géométrie_CORNICHE Extérieure à partir d'un profil - Décalage: 0; Angle: 0 deg; Symétrie: no; Fermer: no; sets with these values: 2
IFC_Pset_Géométrie_BASE Extérieure à partir d'un profil - Angle: 0 deg; Symétrie: no; Côté: 0 cm; sets with these values: 2
IFC_Pset_Géométrie_1° MENUISERIE - Position: Centre; Décalage: 3.5 cm
IFC_Pset_Géométrie_2° MENUISERIE - Décalage: 0 cm
IFC_Pset_Géométrie - Côté extérieur: 0; Invertir (dte/gche): no; Invertir (intérieur/extérieur): no; Largeur: 108.814 cm; Hauteur: 208 cm; Hauteur 2: 0 cm; Rayon Arc: 0 cm; Rayon Cercle: 0 cm; Demi-axe horizontal: 0 cm; Demi-axe vertical: 0 cm
IFC_Pset_Géométrie_GRILLE - décalage: 0 cm; Offset latéral: 0 cm; Décalage supérieur: 0 cm; Décalage inférieur: 0 cm; Nombre accrochages latéraux: 0; Nombre d'accrochages supérieurs: 0; Nombre accrochages inférieurs: 0
IFC_Pset_Système de Référence Altimétrique_INFÉRIEUR - NIVEAU: Niveau 1 (Niveau 1 2343); delta: 0.0128504 cm; sous Niveau: <aucun>
IFC_Pset_Données Métré - Surface 1re Menuiserie: 22600 cm2; Surface Vitre 1re Menuiserie: 0 cm2; Surface du Cadre de la 1re Menuiserie: 1600 cm2; Surface 2e Menuiserie: 0 cm2; Surface Vitre 2e Menuiserie: 0 cm2; Surface du Cadre de la 2ème Menuiserie: 0 cm2; Surface de l'Ouverture: 22600 cm2; Surface de l'Ébrasement: 0 cm2; Surface du Seuil: 0 cm2; Surface du Seuil intérieur: 0 cm2; Volume du seuil: 0 cm3; Volume du seuil intérieur: 0 cm3; Surface de la Grille: 0 cm2; Volume de la Grille: 0 cm3
IFC_Pset_Matériaux_1° MENUISERIE - Cadre externe: Gris de sécurité; Panneau extérieur: Gris de sécurité; Poignée: Aluminium satiné
Pset_DoorCommon - Reference: Porte_2VB[1P] (..\Porte moderne\2 Vantaux Battants\) <aucun>

# IfcDoor: Porte_2VB[1P], Porte 152382
In: Niveau 2
Type - OperationType: DOUBLE_DOOR_SINGLE_SWING; ParameterTakesPrecedence: yes; Sizeable: no; Material: Gris lumière, Aluminium satiné
Type - IfcDoorLiningProperties - LiningDepth: 8 cm; LiningThickness: 3 cm
Type - IfcDoorPanelProperties - PanelDepth: 4 cm; PanelOperation: SWINGING; PanelWidth: 0.5; PanelPosition: LEFT
Description: Porte; OverallHeight: 204 cm; OverallWidth: 85.5366 cm
__RECOGNIZE__ - ID: 152382; TPLG: 102; TPLG_OD: 9005; GENERATE: 1
CTLG_EXTERNAL_LINK - 0, DocType: 3; 0, Tag: 100; 0, Crc: -575706680; 1, DocType: 2; 1, Tag: 0; 1, Crc: -746779066; 2, DocType: 2; 2, Tag: 102; 2, Crc: 1059052754; 3, DocType: 2; 3, Tag: 105; 3, Crc: 1059052754; 4, DocType: 2; 4, Tag: 107; 4, Crc: 1305662025
IFC_PSET_PolygonOffset - polygonOffsetFactor: 2; polygonOffsetUnits: 2
IFC_Pset_Caractéristiques - ID: 152382; Numérotation: 70; Numéro niveau: 05; Titre niveau: Niveau 2; Modèle 1re menuiserie: Porte_2VB[1P]
IFC_Pset_Géométrie_Ébrasement - Présent: no; Côté supérieur: no; Côté INFÉRIEUR: no; Épaisseur extérieure: 0 cm; Épaisseur latérale gauche: 0 cm; Épaisseur latérale droite: 0 cm; Épiasseur latérale supérieure: 0 cm; Épaisseur diagonale gauche: 0 cm; Épaisseur diagonale droite: 0 cm; Épaisseur diagonale inférieure: 0 cm; Épaisseur diagonale supérieure: 0 cm; Épaisseur intérieur: 0 cm
IFC_Pset_Géométrie_Seuil - Type: Aucun; Épaisseur: 0 cm; Épaisseur interne: 0 cm; Décalage séparation: 0 cm; Appui extérieur: 0 cm; Appui intérieur: 0 cm; Côté latéral externe: 0 cm; Côté latéral interne: 0 cm
IFC_Pset_Géométrie_Chambranle - Position: Aucun; Épaisseur Chambranle intérieur: 0 cm; Longueur Chambranle intérieur: 0 cm; Superposition Chambranle intérieur: 0 cm; Épaisseur Intrados: 0 cm; Épaisseur Chambranle extérieur: 0 cm; Largeur Chambranle extérieur: 0 cm; Superposition Chambranle extérieur: 0 cm; Épaisseur Intrados extérieur: 0 cm
IFC_Pset_Géométrie_CORNICHE depuis profil - Position: Aucune; sets with these values: 2
IFC_Pset_Géométrie_CORNICHE Extérieure à partir d'un profil - Décalage: 0; Angle: 0 deg; Symétrie: no; Fermer: no; sets with these values: 2
IFC_Pset_Géométrie_BASE Extérieure à partir d'un profil - Angle: 0 deg; Symétrie: no; Côté: 0 cm; sets with these values: 2
IFC_Pset_Géométrie_1° MENUISERIE - Position: Extérieur; Décalage: 0 cm
IFC_Pset_Géométrie_2° MENUISERIE - Décalage: 0 cm
IFC_Pset_Géométrie - Côté extérieur: 0; Invertir (dte/gche): yes; Invertir (intérieur/extérieur): yes; Largeur: 85.5366 cm; Hauteur: 204 cm; Hauteur 2: 0 cm; Rayon Arc: 0 cm; Rayon Cercle: 0 cm; Demi-axe horizontal: 0 cm; Demi-axe vertical: 0 cm
IFC_Pset_Géométrie_GRILLE - décalage: 0 cm; Offset latéral: 0 cm; Décalage supérieur: 0 cm; Décalage inférieur: 0 cm; Nombre accrochages latéraux: 0; Nombre d'accrochages supérieurs: 0; Nombre accrochages inférieurs: 0
IFC_Pset_Système de Référence Altimétrique_INFÉRIEUR - NIVEAU: Niveau 2 (Niveau 2 13545); delta: 1.37668e-12 cm; sous Niveau: <aucun>
IFC_Pset_Données Métré - Surface 1re Menuiserie: 17400 cm2; Surface Vitre 1re Menuiserie: 0 cm2; Surface du Cadre de la 1re Menuiserie: 1500 cm2; Surface 2e Menuiserie: 0 cm2; Surface Vitre 2e Menuiserie: 0 cm2; Surface du Cadre de la 2ème Menuiserie: 0 cm2; Surface de l'Ouverture: 17400 cm2; Surface de l'Ébrasement: 0 cm2; Surface du Seuil: 0 cm2; Surface du Seuil intérieur: 0 cm2; Volume du seuil: 0 cm3; Volume du seuil intérieur: 0 cm3; Surface de la Grille: 0 cm2; Volume de la Grille: 0 cm3
IFC_Pset_Matériaux_1° MENUISERIE - Cadre externe: Gris lumière; Panneau extérieur: Gris lumière; Poignée: Aluminium satiné
Pset_DoorCommon - Reference: Porte_2VB[1P] (..\Porte moderne\2 Vantaux Battants\) <aucun>

# IfcDoor: Porte_2VB[1P]_tierce, Porte 94964
In: Niveau 1
Type - OperationType: DOUBLE_DOOR_SINGLE_SWING; ParameterTakesPrecedence: yes; Sizeable: no; Material: Blanc gris, Aluminium satiné, Blanc trafic
Type - IfcDoorLiningProperties - LiningDepth: 8 cm; LiningThickness: 3 cm
Type - IfcDoorPanelProperties - PanelDepth: 1 cm; PanelOperation: SWINGING; PanelWidth: 0.6; PanelPosition: LEFT
Description: Porte; OverallHeight: 208 cm; OverallWidth: 150.628 cm
__RECOGNIZE__ - ID: 94964; TPLG: 102; TPLG_OD: 9005; GENERATE: 1
CTLG_EXTERNAL_LINK - 0, DocType: 3; 0, Tag: 100; 0, Crc: -1046271844; 1, DocType: 2; 1, Tag: 0; 1, Crc: -746779066; 2, DocType: 2; 2, Tag: 102; 2, Crc: 2064387956; 3, DocType: 2; 3, Tag: 105; 3, Crc: -848491367; 4, DocType: 2; 4, Tag: 107; 4, Crc: 1305662025
IFC_PSET_PolygonOffset - polygonOffsetFactor: 2; polygonOffsetUnits: 2
IFC_Pset_Caractéristiques - ID: 94964; Numérotation: 40; Numéro niveau: 04; Titre niveau: Niveau 1; Modèle 1re menuiserie: Porte_2VB[1P]_tierce
IFC_Pset_Géométrie_Ébrasement - Présent: no; Côté supérieur: no; Côté INFÉRIEUR: no; Épaisseur extérieure: 0 cm; Épaisseur latérale gauche: 0 cm; Épaisseur latérale droite: 0 cm; Épiasseur latérale supérieure: 0 cm; Épaisseur diagonale gauche: 0 cm; Épaisseur diagonale droite: 0 cm; Épaisseur diagonale inférieure: 0 cm; Épaisseur diagonale supérieure: 0 cm; Épaisseur intérieur: 0 cm
IFC_Pset_Géométrie_Seuil - Type: Aucun; Épaisseur: 0 cm; Épaisseur interne: 0 cm; Décalage séparation: 0 cm; Appui extérieur: 0 cm; Appui intérieur: 0 cm; Côté latéral externe: 0 cm; Côté latéral interne: 0 cm
IFC_Pset_Géométrie_Chambranle - Position: Aucun; Épaisseur Chambranle intérieur: 0 cm; Longueur Chambranle intérieur: 0 cm; Superposition Chambranle intérieur: 0 cm; Épaisseur Intrados: 0 cm; Épaisseur Chambranle extérieur: 0 cm; Largeur Chambranle extérieur: 0 cm; Superposition Chambranle extérieur: 0 cm; Épaisseur Intrados extérieur: 0 cm
IFC_Pset_Géométrie_CORNICHE depuis profil - Position: Aucune; sets with these values: 2
IFC_Pset_Géométrie_CORNICHE Extérieure à partir d'un profil - Décalage: 0; Angle: 0 deg; Symétrie: no; Fermer: no; sets with these values: 2
IFC_Pset_Géométrie_BASE Extérieure à partir d'un profil - Angle: 0 deg; Symétrie: no; Côté: 0 cm; sets with these values: 2
IFC_Pset_Géométrie_1° MENUISERIE - Position: Extérieur; Décalage: 8.5 cm
IFC_Pset_Géométrie_2° MENUISERIE - Décalage: 0 cm
IFC_Pset_Géométrie - Côté extérieur: 0; Invertir (dte/gche): no; Invertir (intérieur/extérieur): yes; Largeur: 150.628 cm; Hauteur: 208 cm; Hauteur 2: 0 cm; Rayon Arc: 0 cm; Rayon Cercle: 0 cm; Demi-axe horizontal: 0 cm; Demi-axe vertical: 0 cm
IFC_Pset_Géométrie_GRILLE - décalage: 0 cm; Offset latéral: 0 cm; Décalage supérieur: 0 cm; Décalage inférieur: 0 cm; Nombre accrochages latéraux: 0; Nombre d'accrochages supérieurs: 0; Nombre accrochages inférieurs: 0
IFC_Pset_Système de Référence Altimétrique_INFÉRIEUR - NIVEAU: Niveau 1 (Niveau 1 2343); delta: 0.0128504 cm; sous Niveau: <aucun>
IFC_Pset_Données Métré - Surface 1re Menuiserie: 31300 cm2; Surface Vitre 1re Menuiserie: 0 cm2; Surface du Cadre de la 1re Menuiserie: 1700 cm2; Surface 2e Menuiserie: 0 cm2; Surface Vitre 2e Menuiserie: 0 cm2; Surface du Cadre de la 2ème Menuiserie: 0 cm2; Surface de l'Ouverture: 31300 cm2; Surface de l'Ébrasement: 0 cm2; Surface du Seuil: 0 cm2; Surface du Seuil intérieur: 0 cm2; Volume du seuil: 0 cm3; Volume du seuil intérieur: 0 cm3; Surface de la Grille: 0 cm2; Volume de la Grille: 0 cm3
IFC_Pset_Matériaux_1° MENUISERIE - Cadre externe: Blanc gris; Panneau extérieur: Blanc trafic; Poignée: Aluminium satiné
Pset_DoorCommon - Reference: Porte_2VB[1P]_tierce (..\Porte moderne\2 Vantaux Battants\) <aucun>

# IfcDoor: Porte_2VB[1P]_tierce, Porte 756288
In: Rez-de-chaussée
Type - OperationType: DOUBLE_DOOR_SINGLE_SWING; ParameterTakesPrecedence: yes; Sizeable: no; Material: Béton (01), Aluminium satiné, Blanc trafic
Type - IfcDoorLiningProperties - LiningDepth: 8 cm; LiningThickness: 3 cm; ThresholdDepth: 30 cm; ThresholdThickness: 3 cm
Type - IfcDoorPanelProperties - PanelDepth: 1 cm; PanelOperation: SWINGING; PanelWidth: 0.6; PanelPosition: LEFT
Description: Porte; OverallHeight: 222.3 cm; OverallWidth: 238.128 cm
__RECOGNIZE__ - ID: 756288; TPLG: 102; TPLG_OD: 9005; GENERATE: 1
CTLG_EXTERNAL_LINK - 0, DocType: 3; 0, Tag: 100; 0, Crc: -1046271844; 1, DocType: 2; 1, Tag: 0; 1, Crc: -746779066; 2, DocType: 2; 2, Tag: 15; 2, Crc: -1434640612; 3, DocType: 2; 3, Tag: 102; 3, Crc: -848491367; 4, DocType: 2; 4, Tag: 105; 4, Crc: -848491367; 5, DocType: 2; 5, Tag: 107; 5, Crc: 1305662025
IFC_PSET_PolygonOffset - polygonOffsetFactor: 2; polygonOffsetUnits: 2
IFC_Pset_Caractéristiques - ID: 756288; Numérotation: 91; Numéro niveau: 03; Titre niveau: Rez-de-chaussée; Modèle 1re menuiserie: Porte_2VB[1P]_tierce
IFC_Pset_Géométrie_Ébrasement - Présent: no; Côté supérieur: no; Côté INFÉRIEUR: no; Épaisseur extérieure: 0 cm; Épaisseur latérale gauche: 0 cm; Épaisseur latérale droite: 0 cm; Épiasseur latérale supérieure: 0 cm; Épaisseur diagonale gauche: 0 cm; Épaisseur diagonale droite: 0 cm; Épaisseur diagonale inférieure: 0 cm; Épaisseur diagonale supérieure: 0 cm; Épaisseur intérieur: 0 cm
IFC_Pset_Géométrie_Seuil - Type: Unique; Épaisseur: 3 cm; Épaisseur interne: 3 cm; Décalage séparation: 0 cm; Appui extérieur: 21 cm; Appui intérieur: 0 cm; Côté latéral externe: 0 cm; Côté latéral interne: 5 cm
IFC_Pset_Géométrie_Chambranle - Position: Aucun; Épaisseur Chambranle intérieur: 0 cm; Longueur Chambranle intérieur: 0 cm; Superposition Chambranle intérieur: 0 cm; Épaisseur Intrados: 0 cm; Épaisseur Chambranle extérieur: 0 cm; Largeur Chambranle extérieur: 0 cm; Superposition Chambranle extérieur: 0 cm; Épaisseur Intrados extérieur: 0 cm
IFC_Pset_Géométrie_CORNICHE depuis profil - Position: Aucune; sets with these values: 2
IFC_Pset_Géométrie_CORNICHE Extérieure à partir d'un profil - Décalage: 0; Angle: 0 deg; Symétrie: no; Fermer: no; sets with these values: 2
IFC_Pset_Géométrie_BASE Extérieure à partir d'un profil - Angle: 0 deg; Symétrie: no; Côté: 0 cm; sets with these values: 2
IFC_Pset_Géométrie_1° MENUISERIE - Position: Intérieur; Décalage: 0 cm
IFC_Pset_Géométrie_2° MENUISERIE - Décalage: 0 cm
IFC_Pset_Géométrie - Côté extérieur: 1; Invertir (dte/gche): yes; Invertir (intérieur/extérieur): no; Largeur: 238.128 cm; Hauteur: 222.3 cm; Hauteur 2: 0 cm; Rayon Arc: 0 cm; Rayon Cercle: 0 cm; Demi-axe horizontal: 0 cm; Demi-axe vertical: 0 cm
IFC_Pset_Géométrie_GRILLE - décalage: 0 cm; Offset latéral: 0 cm; Décalage supérieur: 0 cm; Décalage inférieur: 0 cm; Nombre accrochages latéraux: 0; Nombre d'accrochages supérieurs: 0; Nombre accrochages inférieurs: 0
IFC_Pset_Système de Référence Altimétrique_INFÉRIEUR - NIVEAU: Rez-de-chaussée (Rez-de-chaussée 1047); delta: 0.0128504 cm; sous Niveau: <aucun>
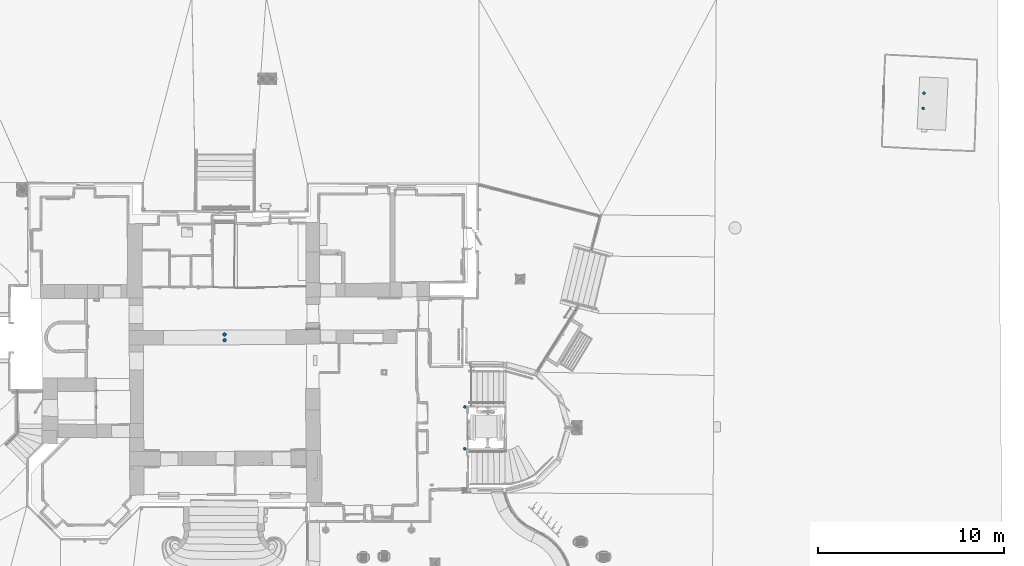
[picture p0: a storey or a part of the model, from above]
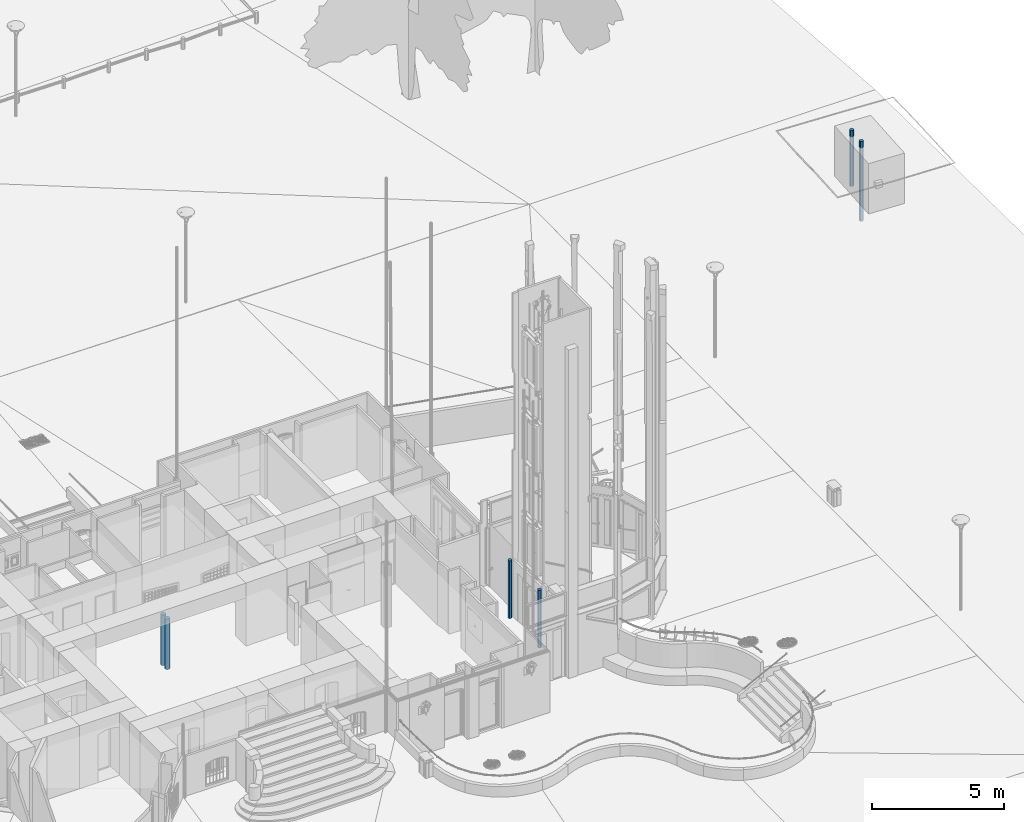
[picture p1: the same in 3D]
Properties of the parts of a building model (IFC2X3), part 8 of 37

# IfcDoor: Porte_2VB[1P]_tierce, Porte 756288
IFC_Pset_Données Métré - Surface 1re Menuiserie: 52900 cm2; Surface Vitre 1re Menuiserie: 0 cm2; Surface du Cadre de la 1re Menuiserie: 2000 cm2; Surface 2e Menuiserie: 0 cm2; Surface Vitre 2e Menuiserie: 0 cm2; Surface du Cadre de la 2ème Menuiserie: 0 cm2; Surface de l'Ouverture: 52900 cm2; Surface de l'Ébrasement: 0 cm2; Surface du Seuil: 7100 cm2; Surface du Seuil intérieur: 0 cm2; Volume du seuil: 20000 cm3; Volume du seuil intérieur: 20000 cm3; Surface de la Grille: 0 cm2; Volume de la Grille: 0 cm3
IFC_Pset_Matériaux - Seuil: Béton (01)
IFC_Pset_Matériaux_1° MENUISERIE - Cadre externe: Blanc trafic; Panneau extérieur: Blanc trafic; Poignée: Aluminium satiné
Pset_DoorCommon - Reference: Porte_2VB[1P]_tierce (..\Porte moderne\2 Vantaux Battants\) <aucun>

# IfcDoor: Porte_2VB[1Pverre]_1IMP verre-extérieur 1 (2)
In: Rez-de-Jardin
Type - ParameterTakesPrecedence: no; Sizeable: no; Material: Transparent, Aluminium mat, Blanc trafic
Type - IfcDoorLiningProperties - LiningDepth: 8 cm; LiningThickness: 3 cm
Description: Porte
__RECOGNIZE__ - TPLG: 102; TPLG_OD: 9005; GENERATE: 1
CTLG_EXTERNAL_LINK - 0, DocType: 3; 0, Tag: 100; 0, Crc: 2124679561; 1, DocType: 2; 1, Tag: 0; 1, Crc: -746779066; 2, DocType: 2; 2, Tag: 102; 2, Crc: -1897652181; 3, DocType: 2; 3, Tag: 104; 3, Crc: -623492449; 4, DocType: 2; 4, Tag: 107; 4, Crc: 913068333
IFC_PSET_PolygonOffset - polygonOffsetFactor: 2; polygonOffsetUnits: 2
IFC_Pset_Caractéristiques - Numéro niveau: 02; Titre niveau: Rez-de-Jardin; Modèle 1re menuiserie: Porte_2VB[1Pverre]_1IMP verre-extérieur 1
IFC_Pset_Géométrie_Ébrasement - Présent: no; Côté supérieur: no; Côté INFÉRIEUR: no; Épaisseur extérieure: 0 cm; Épaisseur latérale gauche: 0 cm; Épaisseur latérale droite: 0 cm; Épiasseur latérale supérieure: 0 cm; Épaisseur diagonale gauche: 0 cm; Épaisseur diagonale droite: 0 cm; Épaisseur diagonale inférieure: 0 cm; Épaisseur diagonale supérieure: 0 cm; Épaisseur intérieur: 0 cm
IFC_Pset_Géométrie_Seuil - Type: Aucun; Épaisseur: 0 cm; Épaisseur interne: 0 cm; Décalage séparation: 0 cm; Appui extérieur: 0 cm; Appui intérieur: 0 cm; Côté latéral externe: 0 cm; Côté latéral interne: 0 cm
IFC_Pset_Géométrie_Chambranle - Position: Aucun; Épaisseur Chambranle intérieur: 0 cm; Longueur Chambranle intérieur: 0 cm; Superposition Chambranle intérieur: 0 cm; Épaisseur Intrados: 0 cm; Épaisseur Chambranle extérieur: 0 cm; Largeur Chambranle extérieur: 0 cm; Superposition Chambranle extérieur: 0 cm; Épaisseur Intrados extérieur: 0 cm
IFC_Pset_Géométrie_CORNICHE depuis profil - Position: Aucune; sets with these values: 2
IFC_Pset_Géométrie_CORNICHE Extérieure à partir d'un profil - Décalage: 0; Angle: 0 deg; Symétrie: no; Fermer: no; sets with these values: 2
IFC_Pset_Géométrie_BASE Extérieure à partir d'un profil - Angle: 0 deg; Symétrie: no; Côté: 0 cm; sets with these values: 2
IFC_Pset_Géométrie_1° MENUISERIE - Décalage: 0 cm
IFC_Pset_Géométrie_2° MENUISERIE - Décalage: 0 cm
IFC_Pset_Géométrie - Côté extérieur: 1; Invertir (dte/gche): yes; Hauteur 2: 0 cm; Rayon Arc: 0 cm; Rayon Cercle: 0 cm; Demi-axe horizontal: 0 cm; Demi-axe vertical: 0 cm
IFC_Pset_Géométrie_GRILLE - décalage: 0 cm; Offset latéral: 0 cm; Décalage supérieur: 0 cm; Décalage inférieur: 0 cm; Nombre accrochages latéraux: 0; Nombre d'accrochages supérieurs: 0; Nombre accrochages inférieurs: 0
IFC_Pset_Système de Référence Altimétrique_INFÉRIEUR - NIVEAU: Rez-de-Jardin (Rez-de-Jardin 15545); sous Niveau: <aucun>
IFC_Pset_Données Métré - Surface 2e Menuiserie: 0 cm2; Surface Vitre 2e Menuiserie: 0 cm2; Surface du Cadre de la 2ème Menuiserie: 0 cm2; Surface de l'Ébrasement: 0 cm2; Surface du Seuil: 0 cm2; Surface du Seuil intérieur: 0 cm2; Volume du seuil: 0 cm3; Volume du seuil intérieur: 0 cm3; Surface de la Grille: 0 cm2; Volume de la Grille: 0 cm3
IFC_Pset_Matériaux_1° MENUISERIE - Cadre externe: Blanc trafic; Verre: Transparent; Poignée: Aluminium mat
Pset_DoorCommon - Reference: Porte_2VB[1Pverre]_1IMP verre-extérieur 1 (..\Porte moderne\2 Vantaux Battants\) <aucun>
Name | OverallHeight (cm) = Hauteur (cm) | OverallWidth (cm) = Largeur (cm) | __RECOGNIZE__, ID = IFC_Pset_Caractéristiques, ID | Numérotation | Position | Invertir (intérieur/extérieur) | delta (cm) | Surface 1re Menuiserie (cm2) = Surface de l'Ouverture (cm2) | Surface Vitre 1re Menuiserie (cm2) | Surface du Cadre de la 1re Menuiserie (cm2)
Porte 73498 | 268 | 153.9 | 73498 | 17 | Extérieur | no | -7.99361e-13 | 41200 | 23700 | 17500
Porte 239017 | 263.999 | 171.672 | 239017 | 86 | Intérieur | yes | -1.95843e-11 | 45300 | 27600 | 17700

# IfcDoor: Porte_2VB[2P verre]_tierce (2)
Type - ParameterTakesPrecedence: no; Sizeable: no; Material: Transparent, Aluminium satiné, Blanc trafic
Type - IfcDoorLiningProperties - LiningDepth: 8 cm; LiningThickness: 3 cm
Description: Porte
__RECOGNIZE__ - TPLG: 102; TPLG_OD: 9005; GENERATE: 1
CTLG_EXTERNAL_LINK - 0, DocType: 3; 0, Tag: 100; 0, Crc: 440304077; 1, DocType: 2; 1, Tag: 0; 1, Crc: -746779066; 2, DocType: 2; 2, Tag: 102; 2, Crc: -848491367; 3, DocType: 2; 3, Tag: 104; 3, Crc: -623492449; 4, DocType: 2; 4, Tag: 107; 4, Crc: 1305662025
IFC_PSET_PolygonOffset - polygonOffsetFactor: 2; polygonOffsetUnits: 2
IFC_Pset_Caractéristiques - Modèle 1re menuiserie: Porte_2VB[2P verre]_tierce
IFC_Pset_Géométrie_Ébrasement - Présent: no; Côté supérieur: no; Côté INFÉRIEUR: no; Épaisseur extérieure: 0 cm; Épaisseur latérale gauche: 0 cm; Épaisseur latérale droite: 0 cm; Épiasseur latérale supérieure: 0 cm; Épaisseur diagonale gauche: 0 cm; Épaisseur diagonale droite: 0 cm; Épaisseur diagonale inférieure: 0 cm; Épaisseur diagonale supérieure: 0 cm; Épaisseur intérieur: 0 cm
IFC_Pset_Géométrie_Seuil - Type: Aucun; Épaisseur: 0 cm; Épaisseur interne: 0 cm; Décalage séparation: 0 cm; Appui extérieur: 0 cm; Appui intérieur: 0 cm; Côté latéral externe: 0 cm; Côté latéral interne: 0 cm
IFC_Pset_Géométrie_Chambranle - Position: Aucun; Épaisseur Chambranle intérieur: 0 cm; Longueur Chambranle intérieur: 0 cm; Superposition Chambranle intérieur: 0 cm; Épaisseur Intrados: 0 cm; Épaisseur Chambranle extérieur: 0 cm; Largeur Chambranle extérieur: 0 cm; Superposition Chambranle extérieur: 0 cm; Épaisseur Intrados extérieur: 0 cm
IFC_Pset_Géométrie_CORNICHE depuis profil - Position: Aucune; sets with these values: 2
IFC_Pset_Géométrie_CORNICHE Extérieure à partir d'un profil - Décalage: 0; Angle: 0 deg; Symétrie: no; Fermer: no; sets with these values: 2
IFC_Pset_Géométrie_BASE Extérieure à partir d'un profil - Angle: 0 deg; Symétrie: no; Côté: 0 cm; sets with these values: 2
IFC_Pset_Géométrie_2° MENUISERIE - Décalage: 0 cm
IFC_Pset_Géométrie - Hauteur 2: 0 cm; Rayon Arc: 0 cm; Rayon Cercle: 0 cm; Demi-axe horizontal: 0 cm; Demi-axe vertical: 0 cm
IFC_Pset_Géométrie_GRILLE - décalage: 0 cm; Offset latéral: 0 cm; Décalage supérieur: 0 cm; Décalage inférieur: 0 cm; Nombre accrochages latéraux: 0; Nombre d'accrochages supérieurs: 0; Nombre accrochages inférieurs: 0
IFC_Pset_Système de Référence Altimétrique_INFÉRIEUR - sous Niveau: <aucun>
IFC_Pset_Données Métré - Surface 2e Menuiserie: 0 cm2; Surface Vitre 2e Menuiserie: 0 cm2; Surface du Cadre de la 2ème Menuiserie: 0 cm2; Surface de l'Ébrasement: 0 cm2; Surface du Seuil: 0 cm2; Surface du Seuil intérieur: 0 cm2; Volume du seuil: 0 cm3; Volume du seuil intérieur: 0 cm3; Surface de la Grille: 0 cm2; Volume de la Grille: 0 cm3
IFC_Pset_Matériaux_1° MENUISERIE - Cadre externe: Blanc trafic; Verre: Transparent; Poignée: Aluminium satiné
Pset_DoorCommon - Reference: Porte_2VB[2P verre]_tierce (..\Porte moderne\2 Vantaux Battants\) <aucun>
Name | In | OverallHeight (cm) = Hauteur (cm) | OverallWidth (cm) = Largeur (cm) | __RECOGNIZE__, ID = IFC_Pset_Caractéristiques, ID | Numérotation | Numéro niveau | Titre niveau | Position | Décalage (cm) | Côté extérieur | Invertir (dte/gche) = Invertir (intérieur/extérieur) | NIVEAU | delta (cm) | Surface 1re Menuiserie (cm2) = Surface de l'Ouverture (cm2) | Surface Vitre 1re Menuiserie (cm2) | Surface du Cadre de la 1re Menuiserie (cm2)
Porte 120670 | Niveau 1 | 258.593 | 145.065 | 120670 | 58 | 04 | Niveau 1 | Extérieur | 0 | 1 | yes | Niveau 1 (Niveau 1 2343) | 0.0128504 | 37500 | 28100 | 9500
Porte 151089 | Niveau 2 | 203 | 149.804 | 151089 | 66 | 05 | Niveau 2 | Intérieur | 10 | 0 | no | Niveau 2 (Niveau 2 13545) | 1.93179e-12 | 30400 | 22300 | 8100

# IfcDoor: Porte_2VB[2P verre]_tierce, Porte 152419
In: Niveau 2
Type - ParameterTakesPrecedence: no; Sizeable: no; Material: Transparent, Jaune 255-255-0, Aluminium satiné
Type - IfcDoorLiningProperties - LiningDepth: 8 cm; LiningThickness: 3 cm
Description: Porte; OverallHeight: 202 cm; OverallWidth: 173.654 cm
__RECOGNIZE__ - ID: 152419; TPLG: 102; TPLG_OD: 9005; GENERATE: 1
CTLG_EXTERNAL_LINK - 0, DocType: 3; 0, Tag: 100; 0, Crc: 440304077; 1, DocType: 2; 1, Tag: 0; 1, Crc: -746779066; 2, DocType: 2; 2, Tag: 102; 2, Crc: -799740758; 3, DocType: 2; 3, Tag: 104; 3, Crc: -623492449; 4, DocType: 2; 4, Tag: 107; 4, Crc: 1305662025
IFC_PSET_PolygonOffset - polygonOffsetFactor: 2; polygonOffsetUnits: 2
IFC_Pset_Caractéristiques - ID: 152419; Numérotation: 72; Numéro niveau: 05; Titre niveau: Niveau 2; Modèle 1re menuiserie: Porte_2VB[2P verre]_tierce
IFC_Pset_Géométrie_Ébrasement - Présent: no; Côté supérieur: no; Côté INFÉRIEUR: no; Épaisseur extérieure: 0 cm; Épaisseur latérale gauche: 0 cm; Épaisseur latérale droite: 0 cm; Épiasseur latérale supérieure: 0 cm; Épaisseur diagonale gauche: 0 cm; Épaisseur diagonale droite: 0 cm; Épaisseur diagonale inférieure: 0 cm; Épaisseur diagonale supérieure: 0 cm; Épaisseur intérieur: 0 cm
IFC_Pset_Géométrie_Seuil - Type: Aucun; Épaisseur: 0 cm; Épaisseur interne: 0 cm; Décalage séparation: 0 cm; Appui extérieur: 0 cm; Appui intérieur: 0 cm; Côté latéral externe: 0 cm; Côté latéral interne: 0 cm
IFC_Pset_Géométrie_Chambranle - Position: Aucun; Épaisseur Chambranle intérieur: 0 cm; Longueur Chambranle intérieur: 0 cm; Superposition Chambranle intérieur: 0 cm; Épaisseur Intrados: 0 cm; Épaisseur Chambranle extérieur: 0 cm; Largeur Chambranle extérieur: 0 cm; Superposition Chambranle extérieur: 0 cm; Épaisseur Intrados extérieur: 0 cm
IFC_Pset_Géométrie_CORNICHE depuis profil - Position: Aucune; sets with these values: 2
IFC_Pset_Géométrie_CORNICHE Extérieure à partir d'un profil - Décalage: 0; Angle: 0 deg; Symétrie: no; Fermer: no; sets with these values: 2
IFC_Pset_Géométrie_BASE Extérieure à partir d'un profil - Angle: 0 deg; Symétrie: no; Côté: 0 cm; sets with these values: 2
IFC_Pset_Géométrie_1° MENUISERIE - Position: Extérieur; Décalage: 0 cm
IFC_Pset_Géométrie_2° MENUISERIE - Décalage: 0 cm
IFC_Pset_Géométrie - Côté extérieur: 1; Invertir (dte/gche): yes; Invertir (intérieur/extérieur): yes; Largeur: 173.654 cm; Hauteur: 202 cm; Hauteur 2: 0 cm; Rayon Arc: 0 cm; Rayon Cercle: 0 cm; Demi-axe horizontal: 0 cm; Demi-axe vertical: 0 cm
IFC_Pset_Géométrie_GRILLE - décalage: 0 cm; Offset latéral: 0 cm; Décalage supérieur: 0 cm; Décalage inférieur: 0 cm; Nombre accrochages latéraux: 0; Nombre d'accrochages supérieurs: 0; Nombre accrochages inférieurs: 0
IFC_Pset_Système de Référence Altimétrique_INFÉRIEUR - NIVEAU: Niveau 2 (Niveau 2 13545); delta: 1.04361e-12 cm; sous Niveau: <aucun>
IFC_Pset_Données Métré - Surface 1re Menuiserie: 35100 cm2; Surface Vitre 1re Menuiserie: 26400 cm2; Surface du Cadre de la 1re Menuiserie: 8600 cm2; Surface 2e Menuiserie: 0 cm2; Surface Vitre 2e Menuiserie: 0 cm2; Surface du Cadre de la 2ème Menuiserie: 0 cm2; Surface de l'Ouverture: 35100 cm2; Surface de l'Ébrasement: 0 cm2; Surface du Seuil: 0 cm2; Surface du Seuil intérieur: 0 cm2; Volume du seuil: 0 cm3; Volume du seuil intérieur: 0 cm3; Surface de la Grille: 0 cm2; Volume de la Grille: 0 cm3
IFC_Pset_Matériaux_1° MENUISERIE - Cadre externe: Jaune 255-255-0; Verre: Transparent; Poignée: Aluminium satiné
Pset_DoorCommon - Reference: Porte_2VB[2P verre]_tierce (..\Porte moderne\2 Vantaux Battants\) <aucun>

# IfcDoor: Porte_2VB[2P verre]_tierce, Porte 103106
In: Niveau 1
Type - ParameterTakesPrecedence: no; Sizeable: no; Material: Transparent, Vert clair_porte, Aluminium satiné
Type - IfcDoorLiningProperties - LiningDepth: 8 cm; LiningThickness: 3 cm
Description: Porte; OverallHeight: 208 cm; OverallWidth: 143 cm
__RECOGNIZE__ - ID: 103106; TPLG: 102; TPLG_OD: 9005; GENERATE: 1
CTLG_EXTERNAL_LINK - 0, DocType: 3; 0, Tag: 100; 0, Crc: 440304077; 1, DocType: 2; 1, Tag: 0; 1, Crc: -746779066; 2, DocType: 2; 2, Tag: 102; 2, Crc: -1022614176; 3, DocType: 2; 3, Tag: 104; 3, Crc: -623492449; 4, DocType: 2; 4, Tag: 107; 4, Crc: 1305662025
IFC_PSET_PolygonOffset - polygonOffsetFactor: 2; polygonOffsetUnits: 2
IFC_Pset_Caractéristiques - ID: 103106; Numérotation: 44; Numéro niveau: 04; Titre niveau: Niveau 1; Modèle 1re menuiserie: Porte_2VB[2P verre]_tierce
IFC_Pset_Géométrie_Ébrasement - Présent: no; Côté supérieur: no; Côté INFÉRIEUR: no; Épaisseur extérieure: 0 cm; Épaisseur latérale gauche: 0 cm; Épaisseur latérale droite: 0 cm; Épiasseur latérale supérieure: 0 cm; Épaisseur diagonale gauche: 0 cm; Épaisseur diagonale droite: 0 cm; Épaisseur diagonale inférieure: 0 cm; Épaisseur diagonale supérieure: 0 cm; Épaisseur intérieur: 0 cm
IFC_Pset_Géométrie_Seuil - Type: Aucun; Épaisseur: 0 cm; Épaisseur interne: 0 cm; Décalage séparation: 0 cm; Appui extérieur: 0 cm; Appui intérieur: 0 cm; Côté latéral externe: 0 cm; Côté latéral interne: 0 cm
IFC_Pset_Géométrie_Chambranle - Position: Aucun; Épaisseur Chambranle intérieur: 0 cm; Longueur Chambranle intérieur: 0 cm; Superposition Chambranle intérieur: 0 cm; Épaisseur Intrados: 0 cm; Épaisseur Chambranle extérieur: 0 cm; Largeur Chambranle extérieur: 0 cm; Superposition Chambranle extérieur: 0 cm; Épaisseur Intrados extérieur: 0 cm
IFC_Pset_Géométrie_CORNICHE depuis profil - Position: Aucune; sets with these values: 2
IFC_Pset_Géométrie_CORNICHE Extérieure à partir d'un profil - Décalage: 0; Angle: 0 deg; Symétrie: no; Fermer: no; sets with these values: 2
IFC_Pset_Géométrie_BASE Extérieure à partir d'un profil - Angle: 0 deg; Symétrie: no; Côté: 0 cm; sets with these values: 2
IFC_Pset_Géométrie_1° MENUISERIE - Position: Extérieur; Décalage: 0 cm
IFC_Pset_Géométrie_2° MENUISERIE - Décalage: 0 cm
IFC_Pset_Géométrie - Côté extérieur: 0; Invertir (dte/gche): yes; Invertir (intérieur/extérieur): yes; Largeur: 143 cm; Hauteur: 208 cm; Hauteur 2: 0 cm; Rayon Arc: 0 cm; Rayon Cercle: 0 cm; Demi-axe horizontal: 0 cm; Demi-axe vertical: 0 cm
IFC_Pset_Géométrie_GRILLE - décalage: 0 cm; Offset latéral: 0 cm; Décalage supérieur: 0 cm; Décalage inférieur: 0 cm; Nombre accrochages latéraux: 0; Nombre d'accrochages supérieurs: 0; Nombre accrochages inférieurs: 0
IFC_Pset_Système de Référence Altimétrique_INFÉRIEUR - NIVEAU: Niveau 1 (Niveau 1 2343); delta: 0.0128504 cm; sous Niveau: <aucun>
IFC_Pset_Données Métré - Surface 1re Menuiserie: 29700 cm2; Surface Vitre 1re Menuiserie: 21600 cm2; Surface du Cadre de la 1re Menuiserie: 8100 cm2; Surface 2e Menuiserie: 0 cm2; Surface Vitre 2e Menuiserie: 0 cm2; Surface du Cadre de la 2ème Menuiserie: 0 cm2; Surface de l'Ouverture: 29700 cm2; Surface de l'Ébrasement: 0 cm2; Surface du Seuil: 0 cm2; Surface du Seuil intérieur: 0 cm2; Volume du seuil: 0 cm3; Volume du seuil intérieur: 0 cm3; Surface de la Grille: 0 cm2; Volume de la Grille: 0 cm3
IFC_Pset_Matériaux_1° MENUISERIE - Cadre externe: Vert clair_porte; Verre: Transparent; Poignée: Aluminium satiné
Pset_DoorCommon - Reference: Porte_2VB[2P verre]_tierce (..\Porte moderne\2 Vantaux Battants\) <aucun>

# IfcDoor: Porte_2VB[2P verre]_tierce, Porte 73502
In: Rez-de-Jardin
Type - ParameterTakesPrecedence: no; Sizeable: no; Material: Transparent, Vert clair_porte, Aluminium satiné
Type - IfcDoorLiningProperties - LiningDepth: 8 cm; LiningThickness: 3 cm; CasingThickness: 6 cm; CasingDepth: 1 cm
Description: Porte; OverallHeight: 203 cm; OverallWidth: 149.784 cm
__RECOGNIZE__ - ID: 73502; TPLG: 102; TPLG_OD: 9005; GENERATE: 1
CTLG_EXTERNAL_LINK - 0, DocType: 3; 0, Tag: 100; 0, Crc: 440304077; 1, DocType: 2; 1, Tag: 0; 1, Crc: -746779066; 2, DocType: 2; 2, Tag: 26; 2, Crc: -1022614176; 3, DocType: 2; 3, Tag: 102; 3, Crc: -1022614176; 4, DocType: 2; 4, Tag: 104; 4, Crc: -623492449; 5, DocType: 2; 5, Tag: 107; 5, Crc: 1305662025
IFC_PSET_PolygonOffset - polygonOffsetFactor: 2; polygonOffsetUnits: 2
IFC_Pset_Caractéristiques - ID: 73502; Numérotation: 18; Numéro niveau: 02; Titre niveau: Rez-de-Jardin; Modèle 1re menuiserie: Porte_2VB[2P verre]_tierce
IFC_Pset_Géométrie_Ébrasement - Présent: no; Côté supérieur: no; Côté INFÉRIEUR: no; Épaisseur extérieure: 0 cm; Épaisseur latérale gauche: 0 cm; Épaisseur latérale droite: 0 cm; Épiasseur latérale supérieure: 0 cm; Épaisseur diagonale gauche: 0 cm; Épaisseur diagonale droite: 0 cm; Épaisseur diagonale inférieure: 0 cm; Épaisseur diagonale supérieure: 0 cm; Épaisseur intérieur: 0 cm
IFC_Pset_Géométrie_Seuil - Type: Aucun; Épaisseur: 0 cm; Épaisseur interne: 0 cm; Décalage séparation: 0 cm; Appui extérieur: 0 cm; Appui intérieur: 0 cm; Côté latéral externe: 0 cm; Côté latéral interne: 0 cm
IFC_Pset_Géométrie_Chambranle - Position: Extérieur; Épaisseur Chambranle intérieur: 0 cm; Longueur Chambranle intérieur: 0 cm; Superposition Chambranle intérieur: 0 cm; Épaisseur Intrados: 0 cm; Épaisseur Chambranle extérieur: 1 cm; Largeur Chambranle extérieur: 6 cm; Superposition Chambranle extérieur: 1 cm; Épaisseur Intrados extérieur: 1 cm
IFC_Pset_Géométrie_CORNICHE depuis profil - Position: Aucune; sets with these values: 2
IFC_Pset_Géométrie_CORNICHE Extérieure à partir d'un profil - Décalage: 0; Angle: 0 deg; Symétrie: no; Fermer: no; sets with these values: 2
IFC_Pset_Géométrie_BASE Extérieure à partir d'un profil - Angle: 0 deg; Symétrie: no; Côté: 0 cm; sets with these values: 2
IFC_Pset_Géométrie_1° MENUISERIE - Position: Extérieur; Décalage: 0 cm
IFC_Pset_Géométrie_2° MENUISERIE - Décalage: 0 cm
IFC_Pset_Géométrie - Côté extérieur: 0; Invertir (dte/gche): no; Invertir (intérieur/extérieur): yes; Largeur: 149.784 cm; Hauteur: 203 cm; Hauteur 2: 0 cm; Rayon Arc: 0 cm; Rayon Cercle: 0 cm; Demi-axe horizontal: 0 cm; Demi-axe vertical: 0 cm
IFC_Pset_Géométrie_GRILLE - décalage: 0 cm; Offset latéral: 0 cm; Décalage supérieur: 0 cm; Décalage inférieur: 0 cm; Nombre accrochages latéraux: 0; Nombre d'accrochages supérieurs: 0; Nombre accrochages inférieurs: 0
IFC_Pset_Système de Référence Altimétrique_INFÉRIEUR - NIVEAU: Rez-de-Jardin (Rez-de-Jardin 15545); delta: -1.33227e-13 cm; sous Niveau: <aucun>
IFC_Pset_Données Métré - Surface 1re Menuiserie: 30400 cm2; Surface Vitre 1re Menuiserie: 22300 cm2; Surface du Cadre de la 1re Menuiserie: 8100 cm2; Surface 2e Menuiserie: 0 cm2; Surface Vitre 2e Menuiserie: 0 cm2; Surface du Cadre de la 2ème Menuiserie: 0 cm2; Surface de l'Ouverture: 30400 cm2; Surface de l'Ébrasement: 0 cm2; Surface du Seuil: 0 cm2; Surface du Seuil intérieur: 0 cm2; Volume du seuil: 0 cm3; Volume du seuil intérieur: 0 cm3; Surface de la Grille: 0 cm2; Volume de la Grille: 0 cm3
IFC_Pset_Matériaux - Chambranle Externe: Vert clair_porte
IFC_Pset_Matériaux_1° MENUISERIE - Cadre externe: Vert clair_porte; Verre: Transparent; Poignée: Aluminium satiné
Pset_DoorCommon - Reference: Porte_2VB[2P verre]_tierce (..\Porte moderne\2 Vantaux Battants\) <aucun>

# IfcDoor: Porte_2VC_SIM_1 panneau, Porte 121016
In: Niveau 1
Type - OperationType: DOUBLE_DOOR_SLIDING; ParameterTakesPrecedence: yes; Sizeable: no; Material: Aluminium satiné, Blanc trafic
Type - IfcDoorLiningProperties - LiningDepth: 8 cm; LiningThickness: 3 cm
Type - IfcDoorPanelProperties - PanelDepth: 4 cm; PanelOperation: SLIDING; PanelWidth: 0.5; PanelPosition: LEFT
Description: Porte; OverallHeight: 206.703 cm; OverallWidth: 188.793 cm
__RECOGNIZE__ - ID: 121016; TPLG: 102; TPLG_OD: 9005; GENERATE: 1
CTLG_EXTERNAL_LINK - 0, DocType: 3; 0, Tag: 100; 0, Crc: 225933329; 1, DocType: 2; 1, Tag: 0; 1, Crc: -746779066; 2, DocType: 2; 2, Tag: 102; 2, Crc: -848491367; 3, DocType: 2; 3, Tag: 105; 3, Crc: -848491367; 4, DocType: 2; 4, Tag: 107; 4, Crc: 1305662025
IFC_PSET_PolygonOffset - polygonOffsetFactor: 2; polygonOffsetUnits: 2
IFC_Pset_Caractéristiques - ID: 121016; Numérotation: 59; Numéro niveau: 04; Titre niveau: Niveau 1; Modèle 1re menuiserie: Porte_2VC_SIM_1 panneau
IFC_Pset_Géométrie_Ébrasement - Présent: no; Côté supérieur: no; Côté INFÉRIEUR: no; Épaisseur extérieure: 0 cm; Épaisseur latérale gauche: 0 cm; Épaisseur latérale droite: 0 cm; Épiasseur latérale supérieure: 0 cm; Épaisseur diagonale gauche: 0 cm; Épaisseur diagonale droite: 0 cm; Épaisseur diagonale inférieure: 0 cm; Épaisseur diagonale supérieure: 0 cm; Épaisseur intérieur: 0 cm
IFC_Pset_Géométrie_Seuil - Type: Aucun; Épaisseur: 0 cm; Épaisseur interne: 0 cm; Décalage séparation: 0 cm; Appui extérieur: 0 cm; Appui intérieur: 0 cm; Côté latéral externe: 0 cm; Côté latéral interne: 0 cm
IFC_Pset_Géométrie_Chambranle - Position: Aucun; Épaisseur Chambranle intérieur: 0 cm; Longueur Chambranle intérieur: 0 cm; Superposition Chambranle intérieur: 0 cm; Épaisseur Intrados: 0 cm; Épaisseur Chambranle extérieur: 0 cm; Largeur Chambranle extérieur: 0 cm; Superposition Chambranle extérieur: 0 cm; Épaisseur Intrados extérieur: 0 cm
IFC_Pset_Géométrie_CORNICHE depuis profil - Position: Aucune; sets with these values: 2
IFC_Pset_Géométrie_CORNICHE Extérieure à partir d'un profil - Décalage: 0; Angle: 0 deg; Symétrie: no; Fermer: no; sets with these values: 2
IFC_Pset_Géométrie_BASE Extérieure à partir d'un profil - Angle: 0 deg; Symétrie: no; Côté: 0 cm; sets with these values: 2
IFC_Pset_Géométrie_1° MENUISERIE - Position: Centre; Décalage: 0 cm
IFC_Pset_Géométrie_2° MENUISERIE - Décalage: 0 cm
IFC_Pset_Géométrie - Côté extérieur: 1; Invertir (dte/gche): no; Invertir (intérieur/extérieur): yes; Largeur: 188.793 cm; Hauteur: 206.703 cm; Hauteur 2: 0 cm; Rayon Arc: 0 cm; Rayon Cercle: 0 cm; Demi-axe horizontal: 0 cm; Demi-axe vertical: 0 cm
IFC_Pset_Géométrie_GRILLE - décalage: 0 cm; Offset latéral: 0 cm; Décalage supérieur: 0 cm; Décalage inférieur: 0 cm; Nombre accrochages latéraux: 0; Nombre d'accrochages supérieurs: 0; Nombre accrochages inférieurs: 0
IFC_Pset_Système de Référence Altimétrique_INFÉRIEUR - NIVEAU: Niveau 1 (Niveau 1 2343); delta: 10 cm; sous Niveau: <aucun>
IFC_Pset_Données Métré - Surface 1re Menuiserie: 39000 cm2; Surface Vitre 1re Menuiserie: 0 cm2; Surface du Cadre de la 1re Menuiserie: 9900 cm2; Surface 2e Menuiserie: 0 cm2; Surface Vitre 2e Menuiserie: 0 cm2; Surface du Cadre de la 2ème Menuiserie: 0 cm2; Surface de l'Ouverture: 39000 cm2; Surface de l'Ébrasement: 0 cm2; Surface du Seuil: 0 cm2; Surface du Seuil intérieur: 0 cm2; Volume du seuil: 0 cm3; Volume du seuil intérieur: 0 cm3; Surface de la Grille: 0 cm2; Volume de la Grille: 0 cm3
IFC_Pset_Matériaux_1° MENUISERIE - Cadre externe: Blanc trafic; Panneau extérieur: Blanc trafic; Poignée: Aluminium satiné
Pset_DoorCommon - Reference: Porte_2VC_SIM_1 panneau (..\Porte moderne\2 Vantaux Coulissants Escamotables\) <aucun>

# IfcDoor: Volet roulant [R], Porte 199143
In: Niveau 2
Type - ParameterTakesPrecedence: no; Sizeable: no; Material: Noyer 01
Description: Porte; OverallHeight: 60 cm; OverallWidth: 65.7663 cm
__RECOGNIZE__ - ID: 199143; TPLG: 102; TPLG_OD: 9005; GENERATE: 1
CTLG_EXTERNAL_LINK - 0, DocType: 3; 0, Tag: 100; 0, Crc: 1190147983; 1, DocType: 2; 1, Tag: 0; 1, Crc: -746779066; 2, DocType: 2; 2, Tag: 109; 2, Crc: 507665632; 3, DocType: 2; 3, Tag: 110; 3, Crc: 507665632
IFC_PSET_PolygonOffset - polygonOffsetFactor: 2; polygonOffsetUnits: 2
IFC_Pset_Caractéristiques - ID: 199143; Numérotation: 85; Numéro niveau: 05; Titre niveau: Niveau 2; Modèle 1re menuiserie: Volet roulant [R]
IFC_Pset_Géométrie_Ébrasement - Présent: no; Côté supérieur: no; Côté INFÉRIEUR: no; Épaisseur extérieure: 0 cm; Épaisseur latérale gauche: 0 cm; Épaisseur latérale droite: 0 cm; Épiasseur latérale supérieure: 0 cm; Épaisseur diagonale gauche: 0 cm; Épaisseur diagonale droite: 0 cm; Épaisseur diagonale inférieure: 0 cm; Épaisseur diagonale supérieure: 0 cm; Épaisseur intérieur: 0 cm
IFC_Pset_Géométrie_Seuil - Type: Aucun; Épaisseur: 0 cm; Épaisseur interne: 0 cm; Décalage séparation: 0 cm; Appui extérieur: 0 cm; Appui intérieur: 0 cm; Côté latéral externe: 0 cm; Côté latéral interne: 0 cm
IFC_Pset_Géométrie_Chambranle - Position: Aucun; Épaisseur Chambranle intérieur: 0 cm; Longueur Chambranle intérieur: 0 cm; Superposition Chambranle intérieur: 0 cm; Épaisseur Intrados: 0 cm; Épaisseur Chambranle extérieur: 0 cm; Largeur Chambranle extérieur: 0 cm; Superposition Chambranle extérieur: 0 cm; Épaisseur Intrados extérieur: 0 cm
IFC_Pset_Géométrie_CORNICHE depuis profil - Position: Aucune; sets with these values: 2
IFC_Pset_Géométrie_CORNICHE Extérieure à partir d'un profil - Décalage: 0; Angle: 0 deg; Symétrie: no; Fermer: no; sets with these values: 2
IFC_Pset_Géométrie_BASE Extérieure à partir d'un profil - Angle: 0 deg; Symétrie: no; Côté: 0 cm; sets with these values: 2
IFC_Pset_Géométrie_1° MENUISERIE - Position: Extérieur; Décalage: 0 cm
IFC_Pset_Géométrie_2° MENUISERIE - Décalage: 0 cm
IFC_Pset_Géométrie - Côté extérieur: 1; Invertir (dte/gche): yes; Invertir (intérieur/extérieur): yes; Largeur: 65.7663 cm; Hauteur: 60 cm; Hauteur 2: 0 cm; Rayon Arc: 0 cm; Rayon Cercle: 0 cm; Demi-axe horizontal: 0 cm; Demi-axe vertical: 0 cm
IFC_Pset_Géométrie_GRILLE - décalage: 0 cm; Offset latéral: 0 cm; Décalage supérieur: 0 cm; Décalage inférieur: 0 cm; Nombre accrochages latéraux: 0; Nombre d'accrochages supérieurs: 0; Nombre accrochages inférieurs: 0
IFC_Pset_Système de Référence Altimétrique_INFÉRIEUR - NIVEAU: Niveau 2 (Niveau 2 13545); delta: 7.54952e-13 cm; sous Niveau: <aucun>
IFC_Pset_Données Métré - Surface 1re Menuiserie: 3900 cm2; Surface Vitre 1re Menuiserie: 0 cm2; Surface du Cadre de la 1re Menuiserie: 0 cm2; Surface 2e Menuiserie: 0 cm2; Surface Vitre 2e Menuiserie: 0 cm2; Surface du Cadre de la 2ème Menuiserie: 0 cm2; Surface de l'Ouverture: 3900 cm2; Surface de l'Ébrasement: 0 cm2; Surface du Seuil: 0 cm2; Surface du Seuil intérieur: 0 cm2; Volume du seuil: 0 cm3; Volume du seuil intérieur: 0 cm3; Surface de la Grille: 0 cm2; Volume de la Grille: 0 cm3
IFC_Pset_Matériaux_1° MENUISERIE - Caisson: Noyer 01; Lames de Rideau de fer: Noyer 01
Pset_DoorCommon - Reference: Volet roulant [R] (..\Volet roulant\) <aucun>

# IfcElementAssembly: Type Object (76)
Name | In | PredefinedType | __RECOGNIZE__, ID = IFC_Pset_Caractéristiques, ID | TPLG = TPLG_OD | GENERATE | 0, DocType | 0, Tag | 0, Crc | 1, DocType = polygonOffsetFactor = polygonOffsetUnits | 1, Tag | 1, Crc | Numérotation | Numéro niveau | Titre niveau | Modèle | Largeur (cm) | Hauteur (cm) | NIVEAU | delta (cm) | sous Niveau | Surface (cm2) | Group | 2, DocType | 2, Tag | 2, Crc | Cadre interne
Groupe 1003433 | Default Site | ACCESSORY_ASSEMBLY
Panneau 1527632 | Rez-de-Jardin | USERDEFINED | 1527632 | 872 | 1 | 3 | 1000 | 1164156635 | 2 | 1005 | 913068333 | 52 | 02 | Rez-de-Jardin | Bardage métalique Ascenseur | 37.2 | 221.6 | Rez-de-Jardin (Rez-de-Jardin 15545) | 0 | <aucun> | 8200 | ...de matériaux et couleurs = Aluminium mat; ...de panneaux = Bardage métalique Ascenseur | IFC_Pset_Matériaux - Panneau intérieur: Aluminium mat
Panneau 1527830 | Rez-de-Jardin | USERDEFINED | 1527830 | 872 | 1 | 3 | 1000 | 1164156635 | 2 | 1005 | 913068333 | 53 | 02 | Rez-de-Jardin | Bardage métalique Ascenseur | 108 | 10 | Rez-de-Jardin (Rez-de-Jardin 15545) | 213 | <aucun> | 1100 | ...de matériaux et couleurs = Aluminium mat; ...de panneaux = Bardage métalique Ascenseur | IFC_Pset_Matériaux - Panneau intérieur: Aluminium mat
Panneau 1527631 | Rez-de-Jardin | USERDEFINED | 1527631 | 872 | 1 | 3 | 1000 | 1164156635 | 2 | 1005 | 913068333 | 51 | 02 | Rez-de-Jardin | Bardage métalique Ascenseur | 34.2 | 221.6 | Rez-de-Jardin (Rez-de-Jardin 15545) | 0 | <aucun> | 7600 | ...de matériaux et couleurs = Aluminium mat; ...de panneaux = Bardage métalique Ascenseur | IFC_Pset_Matériaux - Panneau intérieur: Aluminium mat
Panneau 1702010 | Rez-de-Jardin | USERDEFINED | 1702010 | 872 | 1 | 3 | 1000 | -2030216693 | 2 | 1002 | -72692602 | 69 | 02 | Rez-de-Jardin | Panneau [R] Teck | 60 | 92 | Rez-de-Jardin (Rez-de-Jardin 15545) | 63 | <aucun> | 5500 | ...de panneaux = Panneau [R] Teck; ...de matériaux et couleurs = Acier inoxydable opaque; ...de matériaux et couleurs - 1 = Teck | 2 | 1005 | -537911472 | Acier inoxydable opaque | IFC_Pset_Matériaux - Panneau intérieur: Teck
Panneau 294972 | Rez-de-Jardin | USERDEFINED | 294972 | 872 | 1 | 3 | 1000 | 230728540 | 2 | 0 | 913068333 | 13 | 02 | Rez-de-Jardin | Grille caniveau1 | 56 | 75 | Rez-de-Jardin (Rez-de-Jardin 15545) | 147 | extérieur | 4200 | ...de matériaux et couleurs = Aluminium mat; ...de matériaux et couleurs - 1 = Aluminium satiné; ...de matériaux et couleurs - 2 = Aluminium satiné; ...de panneaux = Grille caniveau1 | 2 | 1002 | -1425522035 | Aluminium satiné | CTLG_EXTERNAL_LINK - 3, DocType: 2; 3, Tag: 1012; 3, Crc: -1425522035
Panneau 303645 | Rez-de-Jardin | USERDEFINED | 303645 | 872 | 1 | 3 | 1000 | 230728540 | 2 | 0 | 913068333 | 14 | 02 | Rez-de-Jardin | Grille caniveau1 | 56 | 75 | Rez-de-Jardin (Rez-de-Jardin 15545) | 158 | extérieur | 4200 | ...de matériaux et couleurs = Aluminium mat; ...de matériaux et couleurs - 1 = Aluminium satiné; ...de matériaux et couleurs - 2 = Aluminium satiné; ...de panneaux = Grille caniveau1 | 2 | 1002 | -1425522035 | Aluminium satiné | CTLG_EXTERNAL_LINK - 3, DocType: 2; 3, Tag: 1012; 3, Crc: -1425522035
Panneau 294968 | Rez-de-Jardin | USERDEFINED | 294968 | 872 | 1 | 3 | 1000 | 274510126 | 2 | 1002 | -1206998685 | 11 | 02 | Rez-de-Jardin | Grille ronde Regard | 80 | 60.3812 | Rez-de-Jardin (Rez-de-Jardin 15545) | 107.796 | <aucun> | 3800 | ...de matériaux et couleurs - 1 = Acier; ...de matériaux et couleurs = Acier; ...de panneaux = Grille ronde Regard | 2 | 1012 | -1206998685 | Acier
Panneau 294969 | Rez-de-Jardin | USERDEFINED | 294969 | 872 | 1 | 3 | 1000 | 274510126 | 2 | 1002 | -1206998685 | 12 | 02 | Rez-de-Jardin | Grille ronde Regard | 80 | 60 | Rez-de-Jardin (Rez-de-Jardin 15545) | 107.796 | <aucun> | 3800 | ...de matériaux et couleurs - 1 = Acier; ...de matériaux et couleurs = Acier; ...de panneaux = Grille ronde Regard | 2 | 1012 | -1206998685 | Acier
Panneau 303655 | Rez-de-Jardin | USERDEFINED | 303655 | 872 | 1 | 3 | 1000 | 274510126 | 2 | 1002 | -1206998685 | 15 | 02 | Rez-de-Jardin | Grille ronde Regard | 64.977 | 60.3812 | Rez-de-Jardin (Rez-de-Jardin 15545) | 110 | <aucun> | 3100 | ...de matériaux et couleurs - 1 = Acier; ...de matériaux et couleurs = Acier; ...de panneaux = Grille ronde Regard | 2 | 1012 | -1206998685 | Acier
Panneau 326484 | Rez-de-Jardin | USERDEFINED | 326484 | 872 | 1 | 3 | 1000 | 230728540 | 2 | 0 | 913068333 | 16 | 02 | Rez-de-Jardin | Grille caniveau1 | 50 | 60 | Rez-de-Jardin (Rez-de-Jardin 15545) | 163 | extérieur | 3000 | ...de matériaux et couleurs = Aluminium mat; ...de matériaux et couleurs - 1 = Aluminium satiné; ...de matériaux et couleurs - 2 = Aluminium satiné; ...de panneaux = Grille caniveau1 | 2 | 1002 | -1425522035 | Aluminium satiné | CTLG_EXTERNAL_LINK - 3, DocType: 2; 3, Tag: 1012; 3, Crc: -1425522035
Panneau 326485 | Rez-de-Jardin | USERDEFINED | 326485 | 872 | 1 | 3 | 1000 | 230728540 | 2 | 0 | 913068333 | 17 | 02 | Rez-de-Jardin | Grille caniveau1 | 50 | 60 | Rez-de-Jardin (Rez-de-Jardin 15545) | 163 | extérieur | 3000 | ...de matériaux et couleurs = Aluminium mat; ...de matériaux et couleurs - 1 = Aluminium satiné; ...de matériaux et couleurs - 2 = Aluminium satiné; ...de panneaux = Grille caniveau1 | 2 | 1002 | -1425522035 | Aluminium satiné | CTLG_EXTERNAL_LINK - 3, DocType: 2; 3, Tag: 1012; 3, Crc: -1425522035
Panneau 294967 | Rez-de-Jardin | USERDEFINED | 294967 | 872 | 1 | 3 | 1000 | 274510126 | 2 | 1002 | -1206998685 | 10 | 02 | Rez-de-Jardin | Grille ronde Regard | 64.977 | 60.3812 | Rez-de-Jardin (Rez-de-Jardin 15545) | 107.796 | <aucun> | 3100 | ...de matériaux et couleurs - 1 = Acier; ...de matériaux et couleurs = Acier; ...de panneaux = Grille ronde Regard | 2 | 1012 | -1206998685 | Acier
Panneau 76236 | Rez-de-Jardin | USERDEFINED | 76236 | 872 | 1 | 3 | 1000 | 1605446849 | 2 | 0 | 913068333 | 03 | 02 | Rez-de-Jardin | Claustra | 125 | 165 | Rez-de-Jardin (Rez-de-Jardin 15545) | 0 | <aucun> | 20600 | ...de matériaux et couleurs - 3 = Noyer 01; ...de matériaux et couleurs = Aluminium mat; ...de panneaux = Claustra; ...de matériaux et couleurs - 1 = Noyer 01; ...de matériaux et couleurs - 2 = Orme | 2 | 1002 | -990824515 | Noyer 01 | IFC_Pset_Matériaux - Panneau intérieur: Orme; CTLG_EXTERNAL_LINK - 3, DocType: 2; 3, Tag: 1005; 3, Crc: -989983316; 4, DocType: 2; 4, Tag: 1012; 4, Crc: -990824515
Panneau 92029 | Rez-de-Jardin | USERDEFINED | 92029 | 872 | 1 | 3 | 1000 | 230728540 | 2 | 0 | 913068333 | 04 | 02 | Rez-de-Jardin | Grille caniveau1 | 248 | 14 | Rez-de-Jardin (Rez-de-Jardin 15545) | 50 | extérieur | 3500 | ...de matériaux et couleurs = Aluminium mat; ...de matériaux et couleurs - 1 = Aluminium satiné; ...de matériaux et couleurs - 2 = Aluminium satiné; ...de panneaux = Grille caniveau1 | 2 | 1002 | -1425522035 | Aluminium satiné | CTLG_EXTERNAL_LINK - 3, DocType: 2; 3, Tag: 1012; 3, Crc: -1425522035
Panneau 73504 | Rez-de-Jardin | USERDEFINED | 73504 | 872 | 1 | 3 | 1000 | 962302589 | 2 | 0 | 913068333 | 01 | 02 | Rez-de-Jardin | Grille [R] BC[Q] | 160 | 33 | Rez-de-Jardin (Rez-de-Jardin 15545) | 18 | <aucun> | 5300 | ...de matériaux et couleurs - 1 = Beige; ...de matériaux et couleurs - 2 = Beige; ...de matériaux et couleurs = Aluminium mat; ...de panneaux = Grille [R] BC[Q] | 2 | 1002 | 2035114887 | Beige | CTLG_EXTERNAL_LINK - 3, DocType: 2; 3, Tag: 1012; 3, Crc: 2035114887
Panneau 76235 | Rez-de-Jardin | USERDEFINED | 76235 | 872 | 1 | 3 | 1000 | 1605446849 | 2 | 0 | 913068333 | 02 | 02 | Rez-de-Jardin | Claustra | 156 | 165 | Rez-de-Jardin (Rez-de-Jardin 15545) | 0 | <aucun> | 25700 | ...de matériaux et couleurs - 3 = Noyer 01; ...de matériaux et couleurs = Aluminium mat; ...de panneaux = Claustra; ...de matériaux et couleurs - 1 = Noyer 01; ...de matériaux et couleurs - 2 = Orme | 2 | 1002 | -990824515 | Noyer 01 | IFC_Pset_Matériaux - Panneau intérieur: Orme; CTLG_EXTERNAL_LINK - 3, DocType: 2; 3, Tag: 1005; 3, Crc: -989983316; 4, DocType: 2; 4, Tag: 1012; 4, Crc: -990824515
Panneau 92047 | Rez-de-Jardin | USERDEFINED | 92047 | 872 | 1 | 3 | 1000 | 230728540 | 2 | 0 | 913068333 | 05 | 02 | Rez-de-Jardin | Grille caniveau1 | 98 | 14 | Rez-de-Jardin (Rez-de-Jardin 15545) | 0 | <aucun> | 1400 | ...de matériaux et couleurs = Aluminium mat; ...de matériaux et couleurs - 1 = Aluminium satiné; ...de matériaux et couleurs - 2 = Aluminium satiné; ...de panneaux = Grille caniveau1 | 2 | 1002 | -1425522035 | Aluminium satiné | CTLG_EXTERNAL_LINK - 3, DocType: 2; 3, Tag: 1012; 3, Crc: -1425522035
Panneau 294721 | Rez-de-Jardin | USERDEFINED | 294721 | 872 | 1 | 3 | 1000 | 274510126 | 2 | 1002 | -1206998685 | 08 | 02 | Rez-de-Jardin | Grille ronde Regard | 64.977 | 60.3812 | Rez-de-Jardin (Rez-de-Jardin 15545) | 1 | <aucun> | 3100 | ...de matériaux et couleurs - 1 = Acier; ...de matériaux et couleurs = Acier; ...de panneaux = Grille ronde Regard | 2 | 1012 | -1206998685 | Acier
Panneau 294722 | Rez-de-Jardin | USERDEFINED | 294722 | 872 | 1 | 3 | 1000 | 274510126 | 2 | 1002 | -1206998685 | 09 | 02 | Rez-de-Jardin | Grille ronde Regard | 64.977 | 60.3812 | Rez-de-Jardin (Rez-de-Jardin 15545) | 1 | <aucun> | 3100 | ...de matériaux et couleurs - 1 = Acier; ...de matériaux et couleurs = Acier; ...de panneaux = Grille ronde Regard | 2 | 1012 | -1206998685 | Acier
Panneau 134273 | Rez-de-Jardin | USERDEFINED | 134273 | 872 | 1 | 3 | 1000 | 230728540 | 2 | 0 | 913068333 | 06 | 02 | Rez-de-Jardin | Grille caniveau1 | 50 | 50 | Rez-de-Jardin (Rez-de-Jardin 15545) | 48 | extérieur | 2500 | ...de matériaux et couleurs = Aluminium mat; ...de matériaux et couleurs - 1 = Aluminium satiné; ...de matériaux et couleurs - 2 = Aluminium satiné; ...de panneaux = Grille caniveau1 | 2 | 1002 | -1425522035 | Aluminium satiné | CTLG_EXTERNAL_LINK - 3, DocType: 2; 3, Tag: 1012; 3, Crc: -1425522035
Panneau 294718 | Rez-de-Jardin | USERDEFINED | 294718 | 872 | 1 | 3 | 1000 | 230728540 | 2 | 0 | 913068333 | 07 | 02 | Rez-de-Jardin | Grille caniveau1 | 50 | 50 | Rez-de-Jardin (Rez-de-Jardin 15545) | 2 | extérieur | 2500 | ...de matériaux et couleurs = Aluminium mat; ...de matériaux et couleurs - 1 = Aluminium satiné; ...de matériaux et couleurs - 2 = Aluminium satiné; ...de panneaux = Grille caniveau1 | 2 | 1002 | -1425522035 | Aluminium satiné | CTLG_EXTERNAL_LINK - 3, DocType: 2; 3, Tag: 1012; 3, Crc: -1425522035
Panneau 1528096 | Rez-de-chaussée | USERDEFINED | 1528096 | 872 | 1 | 3 | 1000 | 1164156635 | 2 | 1005 | 913068333 | 54 | 03 | Rez-de-chaussée | Bardage métalique Ascenseur | 27.5 | 221.6 | Rez-de-chaussée (Rez-de-chaussée 1047) | 0 | <aucun> | 6100 | ...de matériaux et couleurs = Aluminium mat; ...de panneaux = Bardage métalique Ascenseur | IFC_Pset_Matériaux - Panneau intérieur: Aluminium mat
Panneau 1528097 | Rez-de-chaussée | USERDEFINED | 1528097 | 872 | 1 | 3 | 1000 | 1164156635 | 2 | 1005 | 913068333 | 55 | 03 | Rez-de-chaussée | Bardage métalique Ascenseur | 31.5 | 221.6 | Rez-de-chaussée (Rez-de-chaussée 1047) | 0 | <aucun> | 7000 | ...de matériaux et couleurs = Aluminium mat; ...de panneaux = Bardage métalique Ascenseur | IFC_Pset_Matériaux - Panneau intérieur: Aluminium mat
Panneau 1528098 | Rez-de-chaussée | USERDEFINED | 1528098 | 872 | 1 | 3 | 1000 | 1164156635 | 2 | 1005 | 913068333 | 56 | 03 | Rez-de-chaussée | Bardage métalique Ascenseur | 108 | 10 | Rez-de-chaussée (Rez-de-chaussée 1047) | 213 | <aucun> | 1100 | ...de matériaux et couleurs = Aluminium mat; ...de panneaux = Bardage métalique Ascenseur | IFC_Pset_Matériaux - Panneau intérieur: Aluminium mat
Panneau 1702014 | Rez-de-chaussée | USERDEFINED | 1702014 | 872 | 1 | 3 | 1000 | 962302589 | 2 | 0 | 913068333 | 70 | 03 | Rez-de-chaussée | Grille [R] BC[Q] | 163 | 33 | Rez-de-chaussée (Rez-de-chaussée 1047) | 10 | <aucun> | 5400 | ...de matériaux et couleurs = Aluminium mat; ...de panneaux = Grille [R] BC[Q]; ...de matériaux et couleurs - 1 = Aluminium satiné; ...de matériaux et couleurs - 2 = Aluminium satiné | 2 | 1002 | -212966465 | Aluminium satiné | CTLG_EXTERNAL_LINK - 3, DocType: 2; 3, Tag: 1012; 3, Crc: -212966465
Panneau 1702030 | Rez-de-chaussée | USERDEFINED | 1702030 | 872 | 1 | 3 | 1000 | 962302589 | 2 | 0 | 913068333 | 76 | 03 | Rez-de-chaussée | Grille [R] BC[Q] | 145 | 33 | Rez-de-chaussée (Rez-de-chaussée 1047) | 12 | <aucun> | 4800 | ...de matériaux et couleurs = Aluminium mat; ...de panneaux = Grille [R] BC[Q]; ...de matériaux et couleurs - 1 = Aluminium satiné; ...de matériaux et couleurs - 2 = Aluminium satiné | 2 | 1002 | -212966465 | Aluminium satiné | CTLG_EXTERNAL_LINK - 3, DocType: 2; 3, Tag: 1012; 3, Crc: -212966465
Panneau 1702033 | Rez-de-chaussée | USERDEFINED | 1702033 | 872 | 1 | 3 | 1000 | 962302589 | 2 | 0 | 913068333 | 77 | 03 | Rez-de-chaussée | Grille [R] BC[Q] | 142 | 33 | Rez-de-chaussée (Rez-de-chaussée 1047) | 12 | <aucun> | 4700 | ...de matériaux et couleurs = Aluminium mat; ...de panneaux = Grille [R] BC[Q]; ...de matériaux et couleurs - 1 = Aluminium satiné; ...de matériaux et couleurs - 2 = Aluminium satiné | 2 | 1002 | -212966465 | Aluminium satiné | CTLG_EXTERNAL_LINK - 3, DocType: 2; 3, Tag: 1012; 3, Crc: -212966465
Panneau 1528329 | Niveau 1 | USERDEFINED | 1528329 | 872 | 1 | 3 | 1000 | 1164156635 | 2 | 1005 | 913068333 | 57 | 04 | Niveau 1 | Bardage métalique Ascenseur | 28 | 221.6 | Niveau 1 (Niveau 1 2343) | 0 | <aucun> | 6200 | ...de matériaux et couleurs = Aluminium mat; ...de panneaux = Bardage métalique Ascenseur | IFC_Pset_Matériaux - Panneau intérieur: Aluminium mat
Panneau 1528330 | Niveau 1 | USERDEFINED | 1528330 | 872 | 1 | 3 | 1000 | 1164156635 | 2 | 1005 | 913068333 | 58 | 04 | Niveau 1 | Bardage métalique Ascenseur | 31 | 221.6 | Niveau 1 (Niveau 1 2343) | 0 | <aucun> | 6900 | ...de matériaux et couleurs = Aluminium mat; ...de panneaux = Bardage métalique Ascenseur | IFC_Pset_Matériaux - Panneau intérieur: Aluminium mat
Panneau 1702026 | Niveau 1 | USERDEFINED | 1702026 | 872 | 1 | 3 | 1000 | 962302589 | 2 | 0 | 913068333 | 74 | 04 | Niveau 1 | Grille [R] BC[Q] | 145 | 33 | Niveau 1 (Niveau 1 2343) | 10 | <aucun> | 4800 | ...de matériaux et couleurs = Aluminium mat; ...de panneaux = Grille [R] BC[Q]; ...de matériaux et couleurs - 1 = Aluminium satiné; ...de matériaux et couleurs - 2 = Aluminium satiné | 2 | 1002 | -212966465 | Aluminium satiné | CTLG_EXTERNAL_LINK - 3, DocType: 2; 3, Tag: 1012; 3, Crc: -212966465
Panneau 1702029 | Niveau 1 | USERDEFINED | 1702029 | 872 | 1 | 3 | 1000 | 962302589 | 2 | 0 | 913068333 | 75 | 04 | Niveau 1 | Grille [R] BC[Q] | 145 | 33 | Niveau 1 (Niveau 1 2343) | 10 | <aucun> | 4800 | ...de matériaux et couleurs = Aluminium mat; ...de panneaux = Grille [R] BC[Q]; ...de matériaux et couleurs - 1 = Aluminium satiné; ...de matériaux et couleurs - 2 = Aluminium satiné | 2 | 1002 | -212966465 | Aluminium satiné | CTLG_EXTERNAL_LINK - 3, DocType: 2; 3, Tag: 1012; 3, Crc: -212966465
Panneau 1702007 | Niveau 1 | USERDEFINED | 1702007 | 872 | 1 | 3 | 1000 | 962302589 | 2 | 0 | 913068333 | 68 | 04 | Niveau 1 | Grille [R] BC[Q] | 163 | 33 | Niveau 1 (Niveau 1 2343) | 10 | <aucun> | 5400 | ...de matériaux et couleurs = Aluminium mat; ...de panneaux = Grille [R] BC[Q]; ...de matériaux et couleurs - 1 = Aluminium satiné; ...de matériaux et couleurs - 2 = Aluminium satiné | 2 | 1002 | -212966465 | Aluminium satiné | CTLG_EXTERNAL_LINK - 3, DocType: 2; 3, Tag: 1012; 3, Crc: -212966465
Panneau 1528331 | Niveau 1 | USERDEFINED | 1528331 | 872 | 1 | 3 | 1000 | 1164156635 | 2 | 1005 | 913068333 | 59 | 04 | Niveau 1 | Bardage métalique Ascenseur | 107 | 10 | Niveau 1 (Niveau 1 2343) | 214.5 | <aucun> | 1100 | ...de matériaux et couleurs = Aluminium mat; ...de panneaux = Bardage métalique Ascenseur | IFC_Pset_Matériaux - Panneau intérieur: Aluminium mat
Panneau 1702017 | Niveau 2 | USERDEFINED | 1702017 | 872 | 1 | 3 | 1000 | 962302589 | 2 | 0 | 913068333 | 71 | 05 | Niveau 2 | Grille [R] BC[Q] | 163 | 33 | Niveau 2 (Niveau 2 13545) | 12 | <aucun> | 5400 | ...de matériaux et couleurs = Aluminium mat; ...de panneaux = Grille [R] BC[Q]; ...de matériaux et couleurs - 1 = Aluminium satiné; ...de matériaux et couleurs - 2 = Aluminium satiné | 2 | 1002 | -212966465 | Aluminium satiné | CTLG_EXTERNAL_LINK - 3, DocType: 2; 3, Tag: 1012; 3, Crc: -212966465
Panneau 1702022 | Niveau 2 | USERDEFINED | 1702022 | 872 | 1 | 3 | 1000 | 962302589 | 2 | 0 | 913068333 | 72 | 05 | Niveau 2 | Grille [R] BC[Q] | 145 | 33 | Niveau 2 (Niveau 2 13545) | 12 | <aucun> | 4800 | ...de matériaux et couleurs = Aluminium mat; ...de panneaux = Grille [R] BC[Q]; ...de matériaux et couleurs - 1 = Aluminium satiné; ...de matériaux et couleurs - 2 = Aluminium satiné | 2 | 1002 | -212966465 | Aluminium satiné | CTLG_EXTERNAL_LINK - 3, DocType: 2; 3, Tag: 1012; 3, Crc: -212966465
Panneau 1702025 | Niveau 2 | USERDEFINED | 1702025 | 872 | 1 | 3 | 1000 | 962302589 | 2 | 0 | 913068333 | 73 | 05 | Niveau 2 | Grille [R] BC[Q] | 145 | 33 | Niveau 2 (Niveau 2 13545) | 12 | <aucun> | 4800 | ...de matériaux et couleurs = Aluminium mat; ...de panneaux = Grille [R] BC[Q]; ...de matériaux et couleurs - 1 = Aluminium satiné; ...de matériaux et couleurs - 2 = Aluminium satiné | 2 | 1002 | -212966465 | Aluminium satiné | CTLG_EXTERNAL_LINK - 3, DocType: 2; 3, Tag: 1012; 3, Crc: -212966465
Panneau 1528700 | Niveau 2 | USERDEFINED | 1528700 | 872 | 1 | 3 | 1000 | 1164156635 | 2 | 1005 | 913068333 | 61 | 05 | Niveau 2 | Bardage métalique Ascenseur | 31.5 | 221.6 | Niveau 2 (Niveau 2 13545) | 0 | <aucun> | 7000 | ...de matériaux et couleurs = Aluminium mat; ...de panneaux = Bardage métalique Ascenseur | IFC_Pset_Matériaux - Panneau intérieur: Aluminium mat
Panneau 1528701 | Niveau 2 | USERDEFINED | 1528701 | 872 | 1 | 3 | 1000 | 1164156635 | 2 | 1005 | 913068333 | 62 | 05 | Niveau 2 | Bardage métalique Ascenseur | 108 | 10 | Niveau 2 (Niveau 2 13545) | 213 | <aucun> | 1100 | ...de matériaux et couleurs = Aluminium mat; ...de panneaux = Bardage métalique Ascenseur | IFC_Pset_Matériaux - Panneau intérieur: Aluminium mat
Panneau 1528699 | Niveau 2 | USERDEFINED | 1528699 | 872 | 1 | 3 | 1000 | 1164156635 | 2 | 1005 | 913068333 | 60 | 05 | Niveau 2 | Bardage métalique Ascenseur | 28 | 221.6 | Niveau 2 (Niveau 2 13545) | 2 | <aucun> | 6200 | ...de matériaux et couleurs = Aluminium mat; ...de panneaux = Bardage métalique Ascenseur | IFC_Pset_Matériaux - Panneau intérieur: Aluminium mat
Panneau 1519653 | Mezzanine | USERDEFINED | 1519653 | 872 | 1 | 3 | 1000 | 962302589 | 2 | 0 | 913068333 | 50 | 06 | Mezzanine | Grille [R] BC[Q] | 145 | 33 | Mezzanine (Mezzanine 49003) | -220 | <aucun> | 4800 | ...de matériaux et couleurs - 1 = Blanc trafic; ...de matériaux et couleurs - 2 = Blanc trafic; ...de matériaux et couleurs = Aluminium mat; ...de panneaux = Grille [R] BC[Q] | 2 | 1002 | 1192038750 | Blanc trafic | CTLG_EXTERNAL_LINK - 3, DocType: 2; 3, Tag: 1012; 3, Crc: 1192038750
Panneau 1519648 | Mezzanine | USERDEFINED | 1519648 | 872 | 1 | 3 | 1000 | 962302589 | 2 | 0 | 913068333 | 49 | 06 | Mezzanine | Grille [R] BC[Q] | 128 | 33 | Mezzanine (Mezzanine 49003) | -63 | <aucun> | 4200 | ...de matériaux et couleurs - 1 = Blanc trafic; ...de matériaux et couleurs - 2 = Blanc trafic; ...de matériaux et couleurs = Aluminium mat; ...de panneaux = Grille [R] BC[Q] | 2 | 1002 | 1192038750 | Blanc trafic | CTLG_EXTERNAL_LINK - 3, DocType: 2; 3, Tag: 1012; 3, Crc: 1192038750
Panneau 1313605 | Couverture | USERDEFINED | 1313605 | 872 | 1 | 3 | 1000 | -347324662 | 2 | 1002 | -1206998685 | 42 | 07 | Couverture | Panneau verrière 78 x 83cm | 65 | 96 | Couverture (Couverture 2134) | -255 | <aucun> | 6200 | ...de matériaux et couleurs - 1 = Transparent; ...de panneaux = Panneau verrière 78 x 83cm; ...de matériaux et couleurs = Acier | 2 | 1004 | -623492449 | Acier | IFC_Pset_Matériaux - Panneau extérieur: Transparent
Panneau 1313606 | Couverture | USERDEFINED | 1313606 | 872 | 1 | 3 | 1000 | -347324662 | 2 | 1002 | -1206998685 | 43 | 07 | Couverture | Panneau verrière 78 x 83cm | 65 | 96 | Couverture (Couverture 2134) | -255 | <aucun> | 6200 | ...de matériaux et couleurs - 1 = Transparent; ...de panneaux = Panneau verrière 78 x 83cm; ...de matériaux et couleurs = Acier | 2 | 1004 | -623492449 | Acier | IFC_Pset_Matériaux - Panneau extérieur: Transparent
Panneau 1313603 | Couverture | USERDEFINED | 1313603 | 872 | 1 | 3 | 1000 | -347324662 | 2 | 1002 | -1206998685 | 40 | 07 | Couverture | Panneau verrière 78 x 83cm | 75 | 96 | Couverture (Couverture 2134) | -255 | <aucun> | 7200 | ...de matériaux et couleurs - 1 = Transparent; ...de panneaux = Panneau verrière 78 x 83cm; ...de matériaux et couleurs = Acier | 2 | 1004 | -623492449 | Acier | IFC_Pset_Matériaux - Panneau extérieur: Transparent
Panneau 1313604 | Couverture | USERDEFINED | 1313604 | 872 | 1 | 3 | 1000 | -347324662 | 2 | 1002 | -1206998685 | 41 | 07 | Couverture | Panneau verrière 78 x 83cm | 65 | 96 | Couverture (Couverture 2134) | -255 | <aucun> | 6200 | ...de matériaux et couleurs - 1 = Transparent; ...de panneaux = Panneau verrière 78 x 83cm; ...de matériaux et couleurs = Acier | 2 | 1004 | -623492449 | Acier | IFC_Pset_Matériaux - Panneau extérieur: Transparent
Panneau 1313607 | Couverture | USERDEFINED | 1313607 | 872 | 1 | 3 | 1000 | -347324662 | 2 | 1002 | -1206998685 | 44 | 07 | Couverture | Panneau verrière 78 x 83cm | 70 | 96 | Couverture (Couverture 2134) | -192.5 | <aucun> | 6700 | ...de matériaux et couleurs - 1 = Transparent; ...de panneaux = Panneau verrière 78 x 83cm; ...de matériaux et couleurs = Acier | 2 | 1004 | -623492449 | Acier | IFC_Pset_Matériaux - Panneau extérieur: Transparent
Panneau 1314473 | Couverture | USERDEFINED | 1314473 | 872 | 1 | 3 | 1000 | -347324662 | 2 | 1002 | -1206998685 | 47 | 07 | Couverture | Panneau verrière 78 x 83cm | 92 | 135 | Couverture (Couverture 2134) | -165 | <aucun> | 12400 | ...de matériaux et couleurs - 1 = Transparent; ...de panneaux = Panneau verrière 78 x 83cm; ...de matériaux et couleurs = Acier | 2 | 1004 | -623492449 | Acier | IFC_Pset_Matériaux - Panneau extérieur: Transparent
Panneau 1314474 | Couverture | USERDEFINED | 1314474 | 872 | 1 | 3 | 1000 | -347324662 | 2 | 1002 | -1206998685 | 48 | 07 | Couverture | Panneau verrière 78 x 83cm | 92 | 134 | Couverture (Couverture 2134) | -165 | <aucun> | 12300 | ...de matériaux et couleurs - 1 = Transparent; ...de panneaux = Panneau verrière 78 x 83cm; ...de matériaux et couleurs = Acier | 2 | 1004 | -623492449 | Acier | IFC_Pset_Matériaux - Panneau extérieur: Transparent
Panneau 1313608 | Couverture | USERDEFINED | 1313608 | 872 | 1 | 3 | 1000 | -347324662 | 2 | 1002 | -1206998685 | 45 | 07 | Couverture | Panneau verrière 78 x 83cm | 65 | 96 | Couverture (Couverture 2134) | -192.5 | <aucun> | 6200 | ...de matériaux et couleurs - 1 = Transparent; ...de panneaux = Panneau verrière 78 x 83cm; ...de matériaux et couleurs = Acier | 2 | 1004 | -623492449 | Acier | IFC_Pset_Matériaux - Panneau extérieur: Transparent
Panneau 1313609 | Couverture | USERDEFINED | 1313609 | 872 | 1 | 3 | 1000 | -347324662 | 2 | 1002 | -1206998685 | 46 | 07 | Couverture | Panneau verrière 78 x 83cm | 65 | 96 | Couverture (Couverture 2134) | -192.5 | <aucun> | 6200 | ...de matériaux et couleurs - 1 = Transparent; ...de panneaux = Panneau verrière 78 x 83cm; ...de matériaux et couleurs = Acier | 2 | 1004 | -623492449 | Acier | IFC_Pset_Matériaux - Panneau extérieur: Transparent
Panneau 1533944 | Couverture | USERDEFINED | 1533944 | 872 | 1 | 3 | 1000 | -226095368 | 2 | 1002 | -72692602 | 63 | 07 | Couverture | Panneau triangulaire_1 | 100 | 200 | Couverture (Couverture 2134) | -270 | <aucun> | 7300 | ...de matériaux et couleurs - 1 = Transparent; ...de matériaux et couleurs = Acier inoxydable opaque; ...de panneaux = Panneau triangulaire_1 | 2 | 1004 | -623492449 | Acier inoxydable opaque | IFC_Pset_Matériaux - Panneau extérieur: Transparent
Panneau 1533947 | Couverture | USERDEFINED | 1533947 | 872 | 1 | 3 | 1000 | 1269160515 | 2 | 1002 | -72692602 | 66 | 07 | Couverture | Panneau trapézoïdale_1 | 100 | 200 | Couverture (Couverture 2134) | -268 | <aucun> | 6000 | ...de matériaux et couleurs - 1 = Transparent; ...de matériaux et couleurs = Acier inoxydable opaque; ...de panneaux = Panneau trapézoïdale_1 | 2 | 1004 | -623492449 | Acier inoxydable opaque | IFC_Pset_Matériaux - Panneau extérieur: Transparent
Panneau 1533948 | Couverture | USERDEFINED | 1533948 | 872 | 1 | 3 | 1000 | 1269160515 | 2 | 1002 | -72692602 | 67 | 07 | Couverture | Panneau trapézoïdale_1 | 100 | 200 | Couverture (Couverture 2134) | -265 | <aucun> | 6000 | ...de matériaux et couleurs - 1 = Transparent; ...de matériaux et couleurs = Acier inoxydable opaque; ...de panneaux = Panneau trapézoïdale_1 | 2 | 1004 | -623492449 | Acier inoxydable opaque | IFC_Pset_Matériaux - Panneau extérieur: Transparent
Panneau 1533945 | Couverture | USERDEFINED | 1533945 | 872 | 1 | 3 | 1000 | -226095368 | 2 | 1002 | -72692602 | 64 | 07 | Couverture | Panneau triangulaire_1 | 100 | 200 | Couverture (Couverture 2134) | -270 | <aucun> | 7300 | ...de matériaux et couleurs - 1 = Transparent; ...de matériaux et couleurs = Acier inoxydable opaque; ...de panneaux = Panneau triangulaire_1 | 2 | 1004 | -623492449 | Acier inoxydable opaque | IFC_Pset_Matériaux - Panneau extérieur: Transparent
Panneau 1533946 | Couverture | USERDEFINED | 1533946 | 872 | 1 | 3 | 1000 | -1089051250 | 2 | 1002 | -72692602 | 65 | 07 | Couverture | Panneau triangulaire+base_1 | 100 | 200 | Couverture (Couverture 2134) | -200 | <aucun> | 15700 | ...de matériaux et couleurs - 1 = Transparent; ...de matériaux et couleurs = Acier inoxydable opaque; ...de panneaux = Panneau triangulaire+base_1 | 2 | 1004 | -623492449 | Acier inoxydable opaque | IFC_Pset_Matériaux - Panneau extérieur: Transparent
Panneau 1313602 | Couverture | USERDEFINED | 1313602 | 872 | 1 | 3 | 1000 | -347324662 | 2 | 1002 | -1206998685 | 39 | 07 | Couverture | Panneau verrière 78 x 83cm | 75 | 96 | Couverture (Couverture 2134) | -255 | <aucun> | 7200 | ...de matériaux et couleurs - 1 = Transparent; ...de panneaux = Panneau verrière 78 x 83cm; ...de matériaux et couleurs = Acier | 2 | 1004 | -623492449 | Acier | IFC_Pset_Matériaux - Panneau extérieur: Transparent
Panneau 1313353 | Couverture | USERDEFINED | 1313353 | 872 | 1 | 3 | 1000 | -347324662 | 2 | 1002 | -1206998685 | 18 | 07 | Couverture | Panneau verrière 78 x 83cm | 78 | 83 | Couverture (Couverture 2134) | -200 | <aucun> | 6500 | ...de matériaux et couleurs - 1 = Transparent; ...de panneaux = Panneau verrière 78 x 83cm; ...de matériaux et couleurs = Acier | 2 | 1004 | -623492449 | Acier | IFC_Pset_Matériaux - Panneau extérieur: Transparent
Panneau 1313354 | Couverture | USERDEFINED | 1313354 | 872 | 1 | 3 | 1000 | -347324662 | 2 | 1002 | -1206998685 | 19 | 07 | Couverture | Panneau verrière 78 x 83cm | 78 | 83 | Couverture (Couverture 2134) | -200 | <aucun> | 6500 | ...de matériaux et couleurs - 1 = Transparent; ...de panneaux = Panneau verrière 78 x 83cm; ...de matériaux et couleurs = Acier | 2 | 1004 | -623492449 | Acier | IFC_Pset_Matériaux - Panneau extérieur: Transparent
Panneau 1313594 | Couverture | USERDEFINED | 1313594 | 872 | 1 | 3 | 1000 | -347324662 | 2 | 1002 | -1206998685 | 32 | 07 | Couverture | Panneau verrière 78 x 83cm | 64 | 96 | Couverture (Couverture 2134) | -192.5 | <aucun> | 6100 | ...de matériaux et couleurs - 1 = Transparent; ...de panneaux = Panneau verrière 78 x 83cm; ...de matériaux et couleurs = Acier | 2 | 1004 | -623492449 | Acier | IFC_Pset_Matériaux - Panneau extérieur: Transparent
Panneau 1313596 | Couverture | USERDEFINED | 1313596 | 872 | 1 | 3 | 1000 | -347324662 | 2 | 1002 | -1206998685 | 33 | 07 | Couverture | Panneau verrière 78 x 83cm | 64 | 96 | Couverture (Couverture 2134) | -255 | <aucun> | 6100 | ...de matériaux et couleurs - 1 = Transparent; ...de panneaux = Panneau verrière 78 x 83cm; ...de matériaux et couleurs = Acier | 2 | 1004 | -623492449 | Acier | IFC_Pset_Matériaux - Panneau extérieur: Transparent
Panneau 1313597 | Couverture | USERDEFINED | 1313597 | 872 | 1 | 3 | 1000 | -347324662 | 2 | 1002 | -1206998685 | 34 | 07 | Couverture | Panneau verrière 78 x 83cm | 72 | 96 | Couverture (Couverture 2134) | -192.5 | <aucun> | 6900 | ...de matériaux et couleurs - 1 = Transparent; ...de panneaux = Panneau verrière 78 x 83cm; ...de matériaux et couleurs = Acier | 2 | 1004 | -623492449 | Acier | IFC_Pset_Matériaux - Panneau extérieur: Transparent
Panneau 1313600 | Couverture | USERDEFINED | 1313600 | 872 | 1 | 3 | 1000 | -347324662 | 2 | 1002 | -1206998685 | 37 | 07 | Couverture | Panneau verrière 78 x 83cm | 72 | 96 | Couverture (Couverture 2134) | -255 | <aucun> | 6900 | ...de matériaux et couleurs - 1 = Transparent; ...de panneaux = Panneau verrière 78 x 83cm; ...de matériaux et couleurs = Acier | 2 | 1004 | -623492449 | Acier | IFC_Pset_Matériaux - Panneau extérieur: Transparent
Panneau 1313601 | Couverture | USERDEFINED | 1313601 | 872 | 1 | 3 | 1000 | -347324662 | 2 | 1002 | -1206998685 | 38 | 07 | Couverture | Panneau verrière 78 x 83cm | 75 | 96 | Couverture (Couverture 2134) | -255 | <aucun> | 7200 | ...de matériaux et couleurs - 1 = Transparent; ...de panneaux = Panneau verrière 78 x 83cm; ...de matériaux et couleurs = Acier | 2 | 1004 | -623492449 | Acier | IFC_Pset_Matériaux - Panneau extérieur: Transparent
Panneau 1313598 | Couverture | USERDEFINED | 1313598 | 872 | 1 | 3 | 1000 | -347324662 | 2 | 1002 | -1206998685 | 35 | 07 | Couverture | Panneau verrière 78 x 83cm | 72 | 96 | Couverture (Couverture 2134) | -192.5 | <aucun> | 6900 | ...de matériaux et couleurs - 1 = Transparent; ...de panneaux = Panneau verrière 78 x 83cm; ...de matériaux et couleurs = Acier | 2 | 1004 | -623492449 | Acier | IFC_Pset_Matériaux - Panneau extérieur: Transparent
Panneau 1313599 | Couverture | USERDEFINED | 1313599 | 872 | 1 | 3 | 1000 | -347324662 | 2 | 1002 | -1206998685 | 36 | 07 | Couverture | Panneau verrière 78 x 83cm | 72 | 96 | Couverture (Couverture 2134) | -255 | <aucun> | 6900 | ...de matériaux et couleurs - 1 = Transparent; ...de panneaux = Panneau verrière 78 x 83cm; ...de matériaux et couleurs = Acier | 2 | 1004 | -623492449 | Acier | IFC_Pset_Matériaux - Panneau extérieur: Transparent
Panneau 1313581 | Couverture | USERDEFINED | 1313581 | 872 | 1 | 3 | 1000 | -347324662 | 2 | 1002 | -1206998685 | 29 | 07 | Couverture | Panneau verrière 78 x 83cm | 27 | 83 | Couverture (Couverture 2134) | 1109.1 | <aucun> | 2200 | ...de matériaux et couleurs - 1 = Transparent; ...de panneaux = Panneau verrière 78 x 83cm; ...de matériaux et couleurs = Acier | 2 | 1004 | -623492449 | Acier | IFC_Pset_Matériaux - Panneau extérieur: Transparent
Panneau 1313357 | Couverture | USERDEFINED | 1313357 | 872 | 1 | 3 | 1000 | -347324662 | 2 | 1002 | -1206998685 | 22 | 07 | Couverture | Panneau verrière 78 x 83cm | 41 | 83 | Couverture (Couverture 2134) | -200 | <aucun> | 3400 | ...de matériaux et couleurs - 1 = Transparent; ...de panneaux = Panneau verrière 78 x 83cm; ...de matériaux et couleurs = Acier | 2 | 1004 | -623492449 | Acier | IFC_Pset_Matériaux - Panneau extérieur: Transparent
Panneau 1313575 | Couverture | USERDEFINED | 1313575 | 872 | 1 | 3 | 1000 | -347324662 | 2 | 1002 | -1206998685 | 23 | 07 | Couverture | Panneau verrière 78 x 83cm | 27 | 83 | Couverture (Couverture 2134) | -200 | <aucun> | 2200 | ...de matériaux et couleurs - 1 = Transparent; ...de panneaux = Panneau verrière 78 x 83cm; ...de matériaux et couleurs = Acier | 2 | 1004 | -623492449 | Acier | IFC_Pset_Matériaux - Panneau extérieur: Transparent
Panneau 1313355 | Couverture | USERDEFINED | 1313355 | 872 | 1 | 3 | 1000 | -347324662 | 2 | 1002 | -1206998685 | 20 | 07 | Couverture | Panneau verrière 78 x 83cm | 75 | 83 | Couverture (Couverture 2134) | -200 | <aucun> | 6200 | ...de matériaux et couleurs - 1 = Transparent; ...de panneaux = Panneau verrière 78 x 83cm; ...de matériaux et couleurs = Acier | 2 | 1004 | -623492449 | Acier | IFC_Pset_Matériaux - Panneau extérieur: Transparent
Panneau 1313356 | Couverture | USERDEFINED | 1313356 | 872 | 1 | 3 | 1000 | -347324662 | 2 | 1002 | -1206998685 | 21 | 07 | Couverture | Panneau verrière 78 x 83cm | 70 | 83 | Couverture (Couverture 2134) | -200 | <aucun> | 5800 | ...de matériaux et couleurs - 1 = Transparent; ...de panneaux = Panneau verrière 78 x 83cm; ...de matériaux et couleurs = Acier | 2 | 1004 | -623492449 | Acier | IFC_Pset_Matériaux - Panneau extérieur: Transparent
Panneau 1313576 | Couverture | USERDEFINED | 1313576 | 872 | 1 | 3 | 1000 | -347324662 | 2 | 1002 | -1206998685 | 24 | 07 | Couverture | Panneau verrière 78 x 83cm | 78 | 83 | Couverture (Couverture 2134) | 1109.59 | <aucun> | 6500 | ...de matériaux et couleurs - 1 = Transparent; ...de panneaux = Panneau verrière 78 x 83cm; ...de matériaux et couleurs = Acier | 2 | 1004 | -623492449 | Acier | IFC_Pset_Matériaux - Panneau extérieur: Transparent
Panneau 1313579 | Couverture | USERDEFINED | 1313579 | 872 | 1 | 3 | 1000 | -347324662 | 2 | 1002 | -1206998685 | 27 | 07 | Couverture | Panneau verrière 78 x 83cm | 70 | 83 | Couverture (Couverture 2134) | 1109.07 | <aucun> | 5800 | ...de matériaux et couleurs - 1 = Transparent; ...de panneaux = Panneau verrière 78 x 83cm; ...de matériaux et couleurs = Acier | 2 | 1004 | -623492449 | Acier | IFC_Pset_Matériaux - Panneau extérieur: Transparent
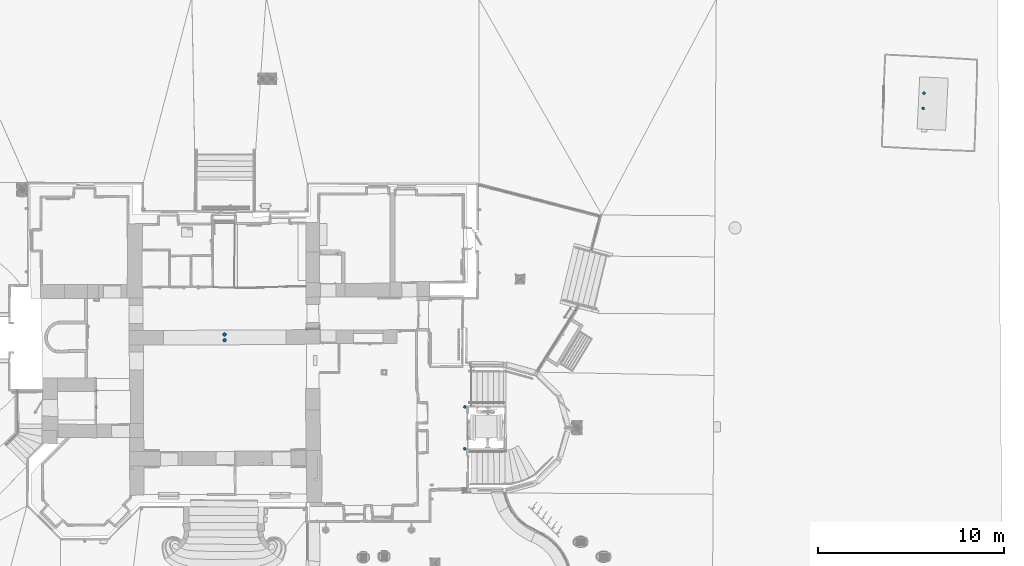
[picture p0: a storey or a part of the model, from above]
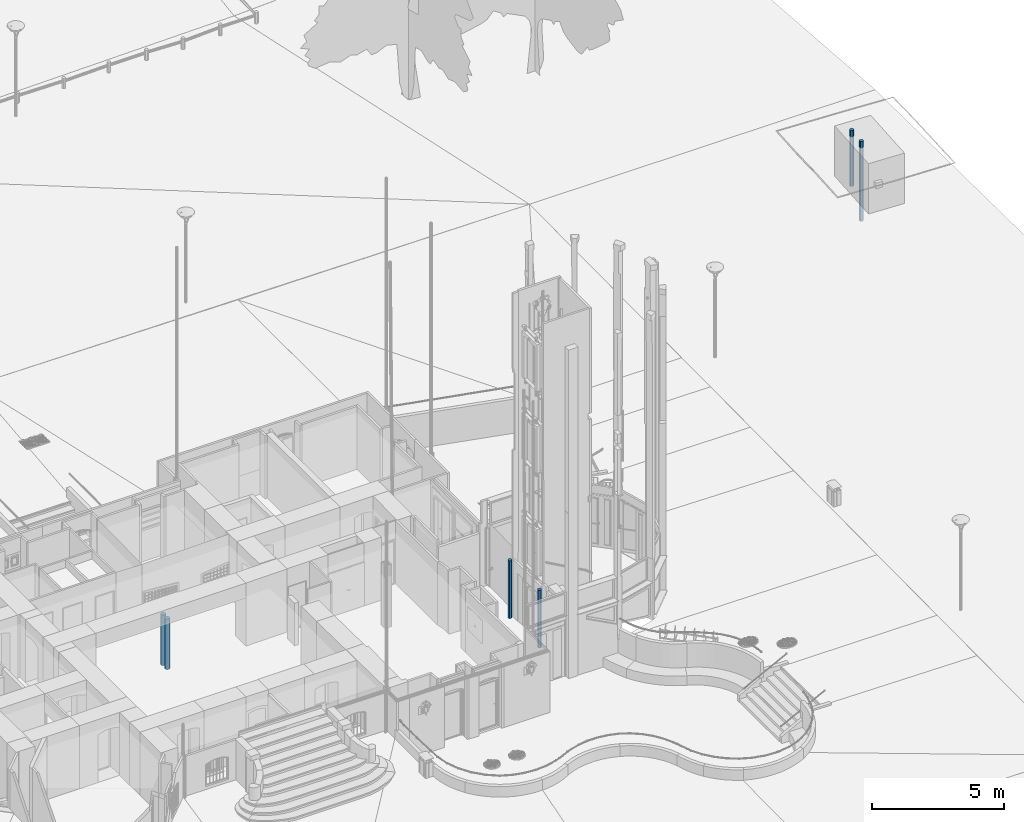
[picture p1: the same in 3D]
Properties of the parts of a building model (IFC2X3), part 9 of 37

# IfcElementAssembly: Type Object (76)
Name | In | PredefinedType | __RECOGNIZE__, ID = IFC_Pset_Caractéristiques, ID | TPLG = TPLG_OD | GENERATE | 0, DocType | 0, Tag | 0, Crc | 1, DocType = polygonOffsetFactor = polygonOffsetUnits | 1, Tag | 1, Crc | Numérotation | Numéro niveau | Titre niveau | Modèle | Largeur (cm) | Hauteur (cm) | NIVEAU | delta (cm) | sous Niveau | Surface (cm2) | Group | 2, DocType | 2, Tag | 2, Crc | Cadre interne
Panneau 1313580 | Couverture | USERDEFINED | 1313580 | 872 | 1 | 3 | 1000 | -347324662 | 2 | 1002 | -1206998685 | 28 | 07 | Couverture | Panneau verrière 78 x 83cm | 41 | 83 | Couverture (Couverture 2134) | 1109.1 | <aucun> | 3400 | ...de matériaux et couleurs - 1 = Transparent; ...de panneaux = Panneau verrière 78 x 83cm; ...de matériaux et couleurs = Acier | 2 | 1004 | -623492449 | Acier | IFC_Pset_Matériaux - Panneau extérieur: Transparent
Panneau 1313577 | Couverture | USERDEFINED | 1313577 | 872 | 1 | 3 | 1000 | -347324662 | 2 | 1002 | -1206998685 | 25 | 07 | Couverture | Panneau verrière 78 x 83cm | 78 | 83 | Couverture (Couverture 2134) | 1109.39 | <aucun> | 6500 | ...de matériaux et couleurs - 1 = Transparent; ...de panneaux = Panneau verrière 78 x 83cm; ...de matériaux et couleurs = Acier | 2 | 1004 | -623492449 | Acier | IFC_Pset_Matériaux - Panneau extérieur: Transparent
Panneau 1313578 | Couverture | USERDEFINED | 1313578 | 872 | 1 | 3 | 1000 | -347324662 | 2 | 1002 | -1206998685 | 26 | 07 | Couverture | Panneau verrière 78 x 83cm | 75 | 83 | Couverture (Couverture 2134) | 1109.28 | <aucun> | 6200 | ...de matériaux et couleurs - 1 = Transparent; ...de panneaux = Panneau verrière 78 x 83cm; ...de matériaux et couleurs = Acier | 2 | 1004 | -623492449 | Acier | IFC_Pset_Matériaux - Panneau extérieur: Transparent

# IfcFlowSegment: Default Flow Segment Type (18)
Type - PredefinedType: GUTTER; Material: Aluminium mat
__RECOGNIZE__ - TPLG: 1740; TPLG_OD: 1740; GENERATE: 1
CTLG_EXTERNAL_LINK - 0, DocType: 2; 0, Tag: 0; 0, Crc: 913068333; 1, DocType: 5; 1, Tag: 0
IFC_PSET_PolygonOffset - polygonOffsetFactor: 2; polygonOffsetUnits: 2
IFC_Pset_Caractéristiques - décalage: [0,00; 0,00] mm; Numérotation: 00
IFC_Pset_Caractéristiques_Profil - Rotation: 0 deg; Symétrie: no
IFC_Pset_Géométrie - Courbe: 50
IFC_Pset_Système de Référence Altimétrique_INFÉRIEUR - sous Niveau: <aucun>
IFC_Pset_Matériaux - Principal: Aluminium mat
Name | In | __RECOGNIZE__, ID = IFC_Pset_Caractéristiques, ID | 1, Crc | Numéro niveau | Titre niveau | Profil = Reference | Hauteur (cm) | Raccord | NIVEAU | delta (cm) | Longueur Totale (cm) | Longueur sans Courbes (cm) | Nombre de Courbes | Développement (Périmètre) (cm) | Diamètre/Côté (cm) | Group
Descente 959295 | Rez-de-Jardin | 959295 | -1690812034 | 02 | Rez-de-Jardin | Profil [CC] Ø100c2mm (..\Profil circulaire creux\) | 1370 | Carré | Rez-de-Jardin (Rez-de-Jardin 15545) | 0 | 1380.6 | 1351.9 | 2 | 31 | 10 | ...de matériaux et couleurs = Aluminium mat; ...de profils et formes = Profil [CC] Ø100c2mm
Descente 959291 | Rez-de-Jardin | 959291 | -1690812034 | 02 | Rez-de-Jardin | Profil [CC] Ø100c2mm (..\Profil circulaire creux\) | 1370 | Carré | Rez-de-Jardin (Rez-de-Jardin 15545) | 0 | 1374.9 | 1365 | 2 | 31 | 10 | ...de matériaux et couleurs = Aluminium mat; ...de profils et formes = Profil [CC] Ø100c2mm
Descente 959294 | Rez-de-Jardin | 959294 | -1690812034 | 02 | Rez-de-Jardin | Profil [CC] Ø100c2mm (..\Profil circulaire creux\) | 1375 | Carré | Rez-de-Jardin (Rez-de-Jardin 15545) | 0 | 1378.1 | 1362.6 | 2 | 31 | 10 | ...de matériaux et couleurs = Aluminium mat; ...de profils et formes = Profil [CC] Ø100c2mm
Descente 1533939 | Rez-de-Jardin | 1533939 | -1690812034 | 02 | Rez-de-Jardin | Profil [CC] Ø100c2mm (..\Profil circulaire creux\) | 1365 | Courbe | Rez-de-Jardin (Rez-de-Jardin 15545) | 0 | 1365 | 1365 | 0 | 31 | 10 | ...de matériaux et couleurs = Aluminium mat; ...de profils et formes = Profil [CC] Ø100c2mm
Descente 1519591 | Rez-de-Jardin | 1519591 | 295231908 | 02 | Rez-de-Jardin | Profil [CC] Ø80c2mm (..\Profil circulaire creux\) | 1363.35 | Courbe | Rez-de-Jardin (Rez-de-Jardin 15545) | 0 | 1394.7 | 1374.7 | 2 | 25 | 8 | ...de matériaux et couleurs = Aluminium mat; ...de profils et formes = Profil [CC] Ø80c2mm
Descente 1533938 | Rez-de-Jardin | 1533938 | 295231908 | 02 | Rez-de-Jardin | Profil [CC] Ø80c2mm (..\Profil circulaire creux\) | 1370 | Courbe | Rez-de-Jardin (Rez-de-Jardin 15545) | 0 | 1370 | 1370 | 0 | 25 | 8 | ...de matériaux et couleurs = Aluminium mat; ...de profils et formes = Profil [CC] Ø80c2mm
Descente 959284 | Rez-de-Jardin | 959284 | -1690812034 | 02 | Rez-de-Jardin | Profil [CC] Ø100c2mm (..\Profil circulaire creux\) | 1364.56 | Carré | Rez-de-Jardin (Rez-de-Jardin 15545) | 0 | 1369.2 | 1359.6 | 2 | 31 | 10 | ...de matériaux et couleurs = Aluminium mat; ...de profils et formes = Profil [CC] Ø100c2mm
Descente 959285 | Rez-de-Jardin | 959285 | -1690812034 | 02 | Rez-de-Jardin | Profil [CC] Ø100c2mm (..\Profil circulaire creux\) | 1364.56 | Carré | Rez-de-Jardin (Rez-de-Jardin 15545) | 0 | 1369.2 | 1359.6 | 2 | 31 | 10 | ...de matériaux et couleurs = Aluminium mat; ...de profils et formes = Profil [CC] Ø100c2mm
Descente 954629 | Rez-de-Jardin | 954629 | 295231908 | 02 | Rez-de-Jardin | Profil [CC] Ø80c2mm (..\Profil circulaire creux\) | 1180.39 | Incliné | Rez-de-Jardin (Rez-de-Jardin 15545) | 0 | 1193.8 | 1180.6 | 2 | 25 | 8 | ...de matériaux et couleurs = Aluminium mat; ...de profils et formes = Profil [CC] Ø80c2mm
Descente 959283 | Rez-de-Jardin | 959283 | 295231908 | 02 | Rez-de-Jardin | Profil [CC] Ø80c2mm (..\Profil circulaire creux\) | 1364.56 | Carré | Rez-de-Jardin (Rez-de-Jardin 15545) | 0 | 1369.2 | 1351.2 | 2 | 25 | 8 | ...de matériaux et couleurs = Aluminium mat; ...de profils et formes = Profil [CC] Ø80c2mm
Descente 959286 | Rez-de-Jardin | 959286 | -1690812034 | 02 | Rez-de-Jardin | Profil [CC] Ø100c2mm (..\Profil circulaire creux\) | 1370 | Carré | Rez-de-Jardin (Rez-de-Jardin 15545) | 0 | 1374.9 | 1365 | 2 | 31 | 10 | ...de matériaux et couleurs = Aluminium mat; ...de profils et formes = Profil [CC] Ø100c2mm
Descente 959289 | Rez-de-Jardin | 959289 | -1690812034 | 02 | Rez-de-Jardin | Profil [CC] Ø100c2mm (..\Profil circulaire creux\) | 1370 | Carré | Rez-de-Jardin (Rez-de-Jardin 15545) | 0 | 1374.9 | 1365 | 2 | 31 | 10 | ...de matériaux et couleurs = Aluminium mat; ...de profils et formes = Profil [CC] Ø100c2mm
Descente 959290 | Rez-de-Jardin | 959290 | -1690812034 | 02 | Rez-de-Jardin | Profil [CC] Ø100c2mm (..\Profil circulaire creux\) | 1375 | Courbe | Rez-de-Jardin (Rez-de-Jardin 15545) | -3.55271e-13 | 1522.3 | 1485.7 | 2 | 31 | 10 | ...de matériaux et couleurs = Aluminium mat; ...de profils et formes = Profil [CC] Ø100c2mm
Descente 959287 | Rez-de-Jardin | 959287 | -1690812034 | 02 | Rez-de-Jardin | Profil [CC] Ø100c2mm (..\Profil circulaire creux\) | 1370 | Carré | Rez-de-Jardin (Rez-de-Jardin 15545) | 0 | 1374.9 | 1365 | 2 | 31 | 10 | ...de matériaux et couleurs = Aluminium mat; ...de profils et formes = Profil [CC] Ø100c2mm
Descente 959288 | Rez-de-Jardin | 959288 | -1690812034 | 02 | Rez-de-Jardin | Profil [CC] Ø100c2mm (..\Profil circulaire creux\) | 1370 | Carré | Rez-de-Jardin (Rez-de-Jardin 15545) | 0 | 1376.5 | 290 | 2 | 31 | 10 | ...de matériaux et couleurs = Aluminium mat; ...de profils et formes = Profil [CC] Ø100c2mm
Descente 1905138 | Niveau 2 | 1905138 | 295231908 | 05 | Niveau 2 | Profil [CC] Ø80c2mm (..\Profil circulaire creux\) | 220 | Courbe | Niveau 2 (Niveau 2 13545) | 0 | 220 | 220 | 0 | 25 | 8 | ...de matériaux et couleurs = Aluminium mat; ...de profils et formes = Profil [CC] Ø80c2mm
Descente 1314528 | Couverture | 1314528 | 295231908 | 07 | Couverture | Profil [CC] Ø80c2mm (..\Profil circulaire creux\) | 175.644 | Courbe | Couverture (Couverture 2134) | -469.72 | 179.1 | 168.9 | 2 | 25 | 8 | ...de matériaux et couleurs = Aluminium mat; ...de profils et formes = Profil [CC] Ø80c2mm
Descente 1314529 | Couverture | 1314529 | 295231908 | 07 | Couverture | Profil [CC] Ø80c2mm (..\Profil circulaire creux\) | 173.257 | Courbe | Couverture (Couverture 2134) | -469.055 | 178 | 166.4 | 2 | 25 | 8 | ...de matériaux et couleurs = Aluminium mat; ...de profils et formes = Profil [CC] Ø80c2mm

# IfcMember (569)
__RECOGNIZE__ - TPLG: 2002; TPLG_OD: 2002; GENERATE: 0
Name | In | Material | ID | Reference | GrossVolume (cm3) | TotalSurfaceArea (cm2)
4294967155 | Rez-de-Jardin | Acier inoxydable opaque | -141 | Dormant | 1752 | 2920
4294967002 | Rez-de-Jardin | Aluminium satiné | -294 | Dormant | 2032 | 3048
4294967001 | Rez-de-Jardin | Aluminium satiné | -295 | Générique | 21.4676 | 52.304
4294967000 | Rez-de-Jardin | Aluminium satiné | -296 | Générique | 83.0313 | 177.331
4294966999 | Rez-de-Jardin | Aluminium satiné | -297 | Générique | 144.595 | 302.357
4294966998 | Rez-de-Jardin | Aluminium satiné | -298 | Générique | 206.159 | 427.384
4294966997 | Rez-de-Jardin | Aluminium satiné | -299 | Générique | 226.367 | 468.424
4294966996 | Rez-de-Jardin | Aluminium satiné | -300 | Générique | 206.158 | 427.384
4294966995 | Rez-de-Jardin | Aluminium satiné | -301 | Générique | 144.595 | 302.357
4294966994 | Rez-de-Jardin | Aluminium satiné | -302 | Générique | 83.0312 | 177.331
4294966993 | Rez-de-Jardin | Aluminium satiné | -303 | Générique | 21.4676 | 52.3041
4294966992 | Rez-de-Jardin | Aluminium satiné | -304 | Générique | 21.4676 | 52.3041
4294966991 | Rez-de-Jardin | Aluminium satiné | -305 | Générique | 83.0313 | 177.331
4294966990 | Rez-de-Jardin | Aluminium satiné | -306 | Générique | 144.595 | 302.357
4294966989 | Rez-de-Jardin | Aluminium satiné | -307 | Générique | 206.159 | 427.384
4294966988 | Rez-de-Jardin | Aluminium satiné | -308 | Générique | 226.367 | 468.424
4294966987 | Rez-de-Jardin | Aluminium satiné | -309 | Générique | 206.159 | 427.384
4294966986 | Rez-de-Jardin | Aluminium satiné | -310 | Générique | 144.595 | 302.357
4294966985 | Rez-de-Jardin | Aluminium satiné | -311 | Générique | 83.0313 | 177.331
4294966984 | Rez-de-Jardin | Aluminium satiné | -312 | Générique | 21.4676 | 52.3041
4294966983 | Rez-de-Jardin | Aluminium satiné | -313 | Dormant | 2032 | 3048
4294966982 | Rez-de-Jardin | Aluminium satiné | -314 | Générique | 21.4676 | 52.304
4294966981 | Rez-de-Jardin | Aluminium satiné | -315 | Générique | 83.0313 | 177.331
4294966980 | Rez-de-Jardin | Aluminium satiné | -316 | Générique | 144.595 | 302.357
4294966979 | Rez-de-Jardin | Aluminium satiné | -317 | Générique | 206.159 | 427.384
4294966978 | Rez-de-Jardin | Aluminium satiné | -318 | Générique | 226.367 | 468.424
4294966977 | Rez-de-Jardin | Aluminium satiné | -319 | Générique | 206.158 | 427.384
4294966976 | Rez-de-Jardin | Aluminium satiné | -320 | Générique | 144.595 | 302.357
4294966975 | Rez-de-Jardin | Aluminium satiné | -321 | Générique | 83.0312 | 177.331
4294966974 | Rez-de-Jardin | Aluminium satiné | -322 | Générique | 21.4676 | 52.3041
4294966973 | Rez-de-Jardin | Aluminium satiné | -323 | Générique | 21.4676 | 52.3041
4294966972 | Rez-de-Jardin | Aluminium satiné | -324 | Générique | 83.0313 | 177.331
4294966971 | Rez-de-Jardin | Aluminium satiné | -325 | Générique | 144.595 | 302.357
4294966970 | Rez-de-Jardin | Aluminium satiné | -326 | Générique | 206.159 | 427.384
4294966969 | Rez-de-Jardin | Aluminium satiné | -327 | Générique | 226.367 | 468.424
4294966968 | Rez-de-Jardin | Aluminium satiné | -328 | Générique | 206.159 | 427.384
4294966967 | Rez-de-Jardin | Aluminium satiné | -329 | Générique | 144.595 | 302.357
4294966966 | Rez-de-Jardin | Aluminium satiné | -330 | Générique | 83.0313 | 177.331
4294966965 | Rez-de-Jardin | Aluminium satiné | -331 | Générique | 21.4676 | 52.3041
4294966964 | Rez-de-Jardin | Acier | -332 | Dormant | 1727.84 | 2591.76
4294966963 | Rez-de-Jardin | Acier | -333 | Générique | 36.9949 | 153.191
4294966962 | Rez-de-Jardin | Acier | -334 | Générique | 60.6107 | 245.401
4294966961 | Rez-de-Jardin | Acier | -335 | Générique | 71.1053 | 286.651
4294966960 | Rez-de-Jardin | Acier | -336 | Générique | 75.4812 | 303.947
4294966959 | Rez-de-Jardin | Acier | -337 | Générique | 75.4812 | 303.947
4294966958 | Rez-de-Jardin | Acier | -338 | Générique | 71.1052 | 286.651
4294966957 | Rez-de-Jardin | Acier | -339 | Générique | 60.6107 | 245.401
4294966956 | Rez-de-Jardin | Acier | -340 | Générique | 36.9948 | 153.191
4294966955 | Rez-de-Jardin | Acier | -341 | Générique | 69.3214 | 197.19
4294966954 | Rez-de-Jardin | Acier | -342 | Générique | 116.182 | 317.176
4294966953 | Rez-de-Jardin | Acier | -343 | Générique | 140.252 | 380.672
4294966952 | Rez-de-Jardin | Acier | -344 | Générique | 156.675 | 424.072
4294966951 | Rez-de-Jardin | Acier | -345 | Générique | 166.078 | 448.938
4294966950 | Rez-de-Jardin | Acier | -346 | Générique | 169.143 | 457.049
4294966949 | Rez-de-Jardin | Acier | -347 | Générique | 166.077 | 448.937
4294966948 | Rez-de-Jardin | Acier | -348 | Générique | 156.675 | 424.072
4294966947 | Rez-de-Jardin | Acier | -349 | Générique | 140.252 | 380.672
4294966946 | Rez-de-Jardin | Acier | -350 | Générique | 116.182 | 317.176
4294966945 | Rez-de-Jardin | Acier | -351 | Générique | 69.3212 | 197.19
4294966944 | Rez-de-Jardin | Acier | -352 | Dormant | 1723.3 | 2584.95
4294966943 | Rez-de-Jardin | Acier | -353 | Générique | 36.1478 | 149.949
4294966942 | Rez-de-Jardin | Acier | -354 | Générique | 60.3313 | 244.327
4294966941 | Rez-de-Jardin | Acier | -355 | Générique | 71.0387 | 286.391
4294966940 | Rez-de-Jardin | Acier | -356 | Générique | 75.4749 | 303.922
4294966939 | Rez-de-Jardin | Acier | -357 | Générique | 75.4751 | 303.923
4294966938 | Rez-de-Jardin | Acier | -358 | Générique | 71.0387 | 286.391
4294966937 | Rez-de-Jardin | Acier | -359 | Générique | 60.3312 | 244.327
4294966936 | Rez-de-Jardin | Acier | -360 | Générique | 36.1478 | 149.949
4294966935 | Rez-de-Jardin | Acier | -361 | Générique | 68.8758 | 195.932
4294966934 | Rez-de-Jardin | Acier | -362 | Générique | 115.295 | 314.779
4294966933 | Rez-de-Jardin | Acier | -363 | Générique | 139.252 | 377.998
4294966932 | Rez-de-Jardin | Acier | -364 | Générique | 155.59 | 421.175
4294966931 | Rez-de-Jardin | Acier | -365 | Générique | 164.948 | 445.925
4294966930 | Rez-de-Jardin | Acier | -366 | Générique | 168 | 454
4294966929 | Rez-de-Jardin | Acier | -367 | Générique | 164.948 | 445.924
4294966928 | Rez-de-Jardin | Acier | -368 | Générique | 155.59 | 421.175
4294966927 | Rez-de-Jardin | Acier | -369 | Générique | 139.252 | 377.998
4294966926 | Rez-de-Jardin | Acier | -370 | Générique | 115.295 | 314.779
4294966925 | Rez-de-Jardin | Acier | -371 | Générique | 68.8759 | 195.932
4294966924 | Rez-de-Jardin | Acier | -372 | Dormant | 1530.21 | 2295.31
4294966923 | Rez-de-Jardin | Acier | -373 | Générique | 30.8435 | 127.807
4294966922 | Rez-de-Jardin | Acier | -374 | Générique | 48.3755 | 196.098
4294966921 | Rez-de-Jardin | Acier | -375 | Générique | 56.8024 | 229.374
4294966920 | Rez-de-Jardin | Acier | -376 | Générique | 60.5288 | 244.132
4294966919 | Rez-de-Jardin | Acier | -377 | Générique | 60.5289 | 244.132
4294966918 | Rez-de-Jardin | Acier | -378 | Générique | 56.8023 | 229.374
4294966917 | Rez-de-Jardin | Acier | -379 | Générique | 48.3755 | 196.098
4294966916 | Rez-de-Jardin | Acier | -380 | Générique | 30.8433 | 127.806
4294966915 | Rez-de-Jardin | Acier | -381 | Générique | 68.5263 | 197.159
4294966914 | Rez-de-Jardin | Acier | -382 | Générique | 124.555 | 340.082
4294966913 | Rez-de-Jardin | Acier | -383 | Générique | 151.01 | 409.239
4294966912 | Rez-de-Jardin | Acier | -384 | Générique | 164.608 | 445.097
4294966911 | Rez-de-Jardin | Acier | -385 | Générique | 169.144 | 457.049
4294966910 | Rez-de-Jardin | Acier | -386 | Générique | 164.608 | 445.097
4294966909 | Rez-de-Jardin | Acier | -387 | Générique | 151.01 | 409.239
4294966908 | Rez-de-Jardin | Acier | -388 | Générique | 124.555 | 340.082
4294966907 | Rez-de-Jardin | Acier | -389 | Générique | 68.5262 | 197.159
4294966902 | Rez-de-Jardin | Aluminium satiné | -394 | Dormant | 1696 | 2544
4294966901 | Rez-de-Jardin | Aluminium satiné | -395 | Générique | 6.54079 | 21.9898
4294966900 | Rez-de-Jardin | Aluminium satiné | -396 | Générique | 68.1044 | 147.017
4294966899 | Rez-de-Jardin | Aluminium satiné | -397 | Générique | 129.668 | 272.043
4294966898 | Rez-de-Jardin | Aluminium satiné | -398 | Générique | 191.232 | 397.07
4294966897 | Rez-de-Jardin | Aluminium satiné | -399 | Générique | 191.232 | 397.07
4294966896 | Rez-de-Jardin | Aluminium satiné | -400 | Générique | 129.668 | 272.043
4294966895 | Rez-de-Jardin | Aluminium satiné | -401 | Générique | 68.1044 | 147.017
4294966894 | Rez-de-Jardin | Aluminium satiné | -402 | Générique | 6.5408 | 21.9898
4294966893 | Rez-de-Jardin | Aluminium satiné | -403 | Générique | 6.54078 | 21.9898
4294966892 | Rez-de-Jardin | Aluminium satiné | -404 | Générique | 68.1044 | 147.016
4294966891 | Rez-de-Jardin | Aluminium satiné | -405 | Générique | 129.668 | 272.043
4294966890 | Rez-de-Jardin | Aluminium satiné | -406 | Générique | 191.232 | 397.07
4294966889 | Rez-de-Jardin | Aluminium satiné | -407 | Générique | 191.232 | 397.07
4294966888 | Rez-de-Jardin | Aluminium satiné | -408 | Générique | 129.668 | 272.043
4294966887 | Rez-de-Jardin | Aluminium satiné | -409 | Générique | 68.1044 | 147.017
4294966886 | Rez-de-Jardin | Aluminium satiné | -410 | Générique | 6.5408 | 21.9898
4294966885 | Rez-de-Jardin | Aluminium satiné | -411 | Dormant | 1696 | 2544
4294966884 | Rez-de-Jardin | Aluminium satiné | -412 | Générique | 6.54079 | 21.9898
4294966883 | Rez-de-Jardin | Aluminium satiné | -413 | Générique | 68.1044 | 147.017
4294966882 | Rez-de-Jardin | Aluminium satiné | -414 | Générique | 129.668 | 272.043
4294966881 | Rez-de-Jardin | Aluminium satiné | -415 | Générique | 191.232 | 397.07
4294966880 | Rez-de-Jardin | Aluminium satiné | -416 | Générique | 191.232 | 397.07
4294966879 | Rez-de-Jardin | Aluminium satiné | -417 | Générique | 129.668 | 272.043
4294966878 | Rez-de-Jardin | Aluminium satiné | -418 | Générique | 68.1044 | 147.017
4294966877 | Rez-de-Jardin | Aluminium satiné | -419 | Générique | 6.5408 | 21.9898
4294966876 | Rez-de-Jardin | Aluminium satiné | -420 | Générique | 6.54078 | 21.9898
4294966875 | Rez-de-Jardin | Aluminium satiné | -421 | Générique | 68.1044 | 147.016
4294966874 | Rez-de-Jardin | Aluminium satiné | -422 | Générique | 129.668 | 272.043
4294966873 | Rez-de-Jardin | Aluminium satiné | -423 | Générique | 191.232 | 397.07
4294966872 | Rez-de-Jardin | Aluminium satiné | -424 | Générique | 191.232 | 397.07
4294966871 | Rez-de-Jardin | Aluminium satiné | -425 | Générique | 129.668 | 272.043
4294966870 | Rez-de-Jardin | Aluminium satiné | -426 | Générique | 68.1044 | 147.017
4294966869 | Rez-de-Jardin | Aluminium satiné | -427 | Générique | 6.5408 | 21.9898
4294966868 | Rez-de-Jardin | Acier | -428 | Dormant | 1530.21 | 2295.31
4294966867 | Rez-de-Jardin | Acier | -429 | Générique | 30.8435 | 127.807
4294966866 | Rez-de-Jardin | Acier | -430 | Générique | 48.3755 | 196.098
4294966865 | Rez-de-Jardin | Acier | -431 | Générique | 56.8024 | 229.374
4294966864 | Rez-de-Jardin | Acier | -432 | Générique | 60.5288 | 244.132
4294966863 | Rez-de-Jardin | Acier | -433 | Générique | 60.5289 | 244.132
4294966862 | Rez-de-Jardin | Acier | -434 | Générique | 56.8023 | 229.374
4294966861 | Rez-de-Jardin | Acier | -435 | Générique | 48.3755 | 196.098
4294966860 | Rez-de-Jardin | Acier | -436 | Générique | 30.8433 | 127.806
4294966859 | Rez-de-Jardin | Acier | -437 | Générique | 68.5263 | 197.159
4294966858 | Rez-de-Jardin | Acier | -438 | Générique | 124.555 | 340.082
4294966857 | Rez-de-Jardin | Acier | -439 | Générique | 151.01 | 409.239
4294966856 | Rez-de-Jardin | Acier | -440 | Générique | 164.608 | 445.097
4294966855 | Rez-de-Jardin | Acier | -441 | Générique | 169.144 | 457.049
4294966854 | Rez-de-Jardin | Acier | -442 | Générique | 164.608 | 445.097
4294966853 | Rez-de-Jardin | Acier | -443 | Générique | 151.01 | 409.239
4294966852 | Rez-de-Jardin | Acier | -444 | Générique | 124.555 | 340.082
4294966851 | Rez-de-Jardin | Acier | -445 | Générique | 68.5262 | 197.159
4294966850 | Rez-de-Jardin | Noyer 01 | -446 | Dormant | 6864 | 5768
4294966849 | Rez-de-Jardin | Noyer 01 | -447 | Dormant | 9483.22 | 6394.38
4294966848 | Rez-de-Jardin | Noyer 01 | -448 | Générique | 212.797 | 356.842
4294966847 | Rez-de-Jardin | Noyer 01 | -449 | Générique | 796.48 | 1092.21
4294966846 | Rez-de-Jardin | Noyer 01 | -450 | Générique | 796.477 | 1092.21
4294966845 | Rez-de-Jardin | Noyer 01 | -451 | Générique | 796.478 | 1092.21
4294966844 | Rez-de-Jardin | Noyer 01 | -452 | Générique | 796.479 | 1092.21
4294966843 | Rez-de-Jardin | Noyer 01 | -453 | Générique | 796.478 | 1092.21
4294966842 | Rez-de-Jardin | Noyer 01 | -454 | Générique | 563.528 | 776.858
4294966841 | Rez-de-Jardin | Noyer 01 | -455 | Générique | 551.814 | 760.998
4294966840 | Rez-de-Jardin | Noyer 01 | -456 | Générique | 540.099 | 745.137
4294966839 | Rez-de-Jardin | Noyer 01 | -457 | Générique | 528.385 | 729.277
4294966838 | Rez-de-Jardin | Noyer 01 | -458 | Générique | 516.67 | 713.416
4294966837 | Rez-de-Jardin | Noyer 01 | -459 | Générique | 504.956 | 697.556
4294966836 | Rez-de-Jardin | Noyer 01 | -460 | Générique | 493.242 | 681.696
4294966835 | Rez-de-Jardin | Noyer 01 | -461 | Générique | 481.527 | 665.836
4294966834 | Rez-de-Jardin | Noyer 01 | -462 | Dormant | 4140 | 2832
4294966832 | Rez-de-Jardin | Aluminium satiné | -464 | Dormant | 4128 | 6192
4294966831 | Rez-de-Jardin | Aluminium satiné | -465 | Générique | 29.5663 | 68.7512
4294966830 | Rez-de-Jardin | Aluminium satiné | -466 | Générique | 43.5321 | 97.1136
4294966829 | Rez-de-Jardin | Aluminium satiné | -467 | Générique | 43.5321 | 97.1136
4294966828 | Rez-de-Jardin | Aluminium satiné | -468 | Générique | 43.5321 | 97.1136
4294966827 | Rez-de-Jardin | Aluminium satiné | -469 | Générique | 43.5321 | 97.1137
4294966826 | Rez-de-Jardin | Aluminium satiné | -470 | Générique | 43.532 | 97.1136
4294966825 | Rez-de-Jardin | Aluminium satiné | -471 | Générique | 43.532 | 97.1136
4294966824 | Rez-de-Jardin | Aluminium satiné | -472 | Générique | 43.5321 | 97.1137
4294966823 | Rez-de-Jardin | Aluminium satiné | -473 | Générique | 43.5321 | 97.1137
4294966822 | Rez-de-Jardin | Aluminium satiné | -474 | Générique | 43.5321 | 97.1137
4294966821 | Rez-de-Jardin | Aluminium satiné | -475 | Générique | 43.532 | 97.1136
4294966820 | Rez-de-Jardin | Aluminium satiné | -476 | Générique | 43.5321 | 97.1137
4294966819 | Rez-de-Jardin | Aluminium satiné | -477 | Générique | 43.5321 | 97.1136
4294966818 | Rez-de-Jardin | Aluminium satiné | -478 | Générique | 43.532 | 97.1136
4294966817 | Rez-de-Jardin | Aluminium satiné | -479 | Générique | 43.532 | 97.1135
4294966816 | Rez-de-Jardin | Aluminium satiné | -480 | Générique | 43.532 | 97.1135
4294966815 | Rez-de-Jardin | Aluminium satiné | -481 | Générique | 43.532 | 97.1136
4294966814 | Rez-de-Jardin | Aluminium satiné | -482 | Générique | 29.5663 | 68.7512
4294966813 | Rez-de-Jardin | Aluminium satiné | -483 | Générique | 29.5662 | 68.7512
4294966812 | Rez-de-Jardin | Aluminium satiné | -484 | Générique | 43.532 | 97.1136
4294966811 | Rez-de-Jardin | Aluminium satiné | -485 | Générique | 43.532 | 97.1135
4294966810 | Rez-de-Jardin | Aluminium satiné | -486 | Générique | 43.532 | 97.1135
4294966809 | Rez-de-Jardin | Aluminium satiné | -487 | Générique | 43.532 | 97.1136
4294966808 | Rez-de-Jardin | Aluminium satiné | -488 | Générique | 43.5321 | 97.1136
4294966807 | Rez-de-Jardin | Aluminium satiné | -489 | Générique | 43.5321 | 97.1137
4294966806 | Rez-de-Jardin | Aluminium satiné | -490 | Générique | 43.532 | 97.1136
4294966805 | Rez-de-Jardin | Aluminium satiné | -491 | Générique | 43.5321 | 97.1137
4294966804 | Rez-de-Jardin | Aluminium satiné | -492 | Générique | 43.5321 | 97.1137
4294966803 | Rez-de-Jardin | Aluminium satiné | -493 | Générique | 43.5321 | 97.1137
4294966802 | Rez-de-Jardin | Aluminium satiné | -494 | Générique | 43.5321 | 97.1136
4294966801 | Rez-de-Jardin | Aluminium satiné | -495 | Générique | 43.532 | 97.1136
4294966800 | Rez-de-Jardin | Aluminium satiné | -496 | Générique | 43.5321 | 97.1137
4294966799 | Rez-de-Jardin | Aluminium satiné | -497 | Générique | 43.5321 | 97.1136
4294966798 | Rez-de-Jardin | Aluminium satiné | -498 | Générique | 43.5321 | 97.1136
4294966797 | Rez-de-Jardin | Aluminium satiné | -499 | Générique | 43.5321 | 97.1136
4294966796 | Rez-de-Jardin | Aluminium satiné | -500 | Générique | 29.5663 | 68.7513
4294966795 | Rez-de-Jardin | Beige | -501 | Dormant | 3024 | 4536
4294966794 | Rez-de-Jardin | Beige | -502 | Générique | 480.197 | 981.365
4294966793 | Rez-de-Jardin | Beige | -503 | Générique | 480.196 | 981.365
4294966792 | Rez-de-Jardin | Beige | -504 | Générique | 480.196 | 981.365
4294966791 | Rez-de-Jardin | Beige | -505 | Générique | 89.2673 | 187.445
4294966790 | Rez-de-Jardin | Beige | -506 | Générique | 89.2673 | 187.445
4294966789 | Rez-de-Jardin | Beige | -507 | Générique | 89.2673 | 187.445
4294966788 | Rez-de-Jardin | Beige | -508 | Générique | 89.2673 | 187.445
4294966787 | Rez-de-Jardin | Beige | -509 | Générique | 89.2673 | 187.445
4294966786 | Rez-de-Jardin | Beige | -510 | Générique | 89.2672 | 187.445
4294966785 | Rez-de-Jardin | Beige | -511 | Générique | 89.2673 | 187.445
4294966784 | Rez-de-Jardin | Beige | -512 | Générique | 89.2671 | 187.445
4294966783 | Rez-de-Jardin | Beige | -513 | Générique | 89.2674 | 187.445
4294966782 | Rez-de-Jardin | Beige | -514 | Générique | 89.2672 | 187.445
4294966781 | Rez-de-Jardin | Beige | -515 | Générique | 89.2673 | 187.445
4294966780 | Rez-de-Jardin | Beige | -516 | Générique | 89.2672 | 187.445
4294966779 | Rez-de-Jardin | Beige | -517 | Générique | 89.267 | 187.445
4294966778 | Rez-de-Jardin | Beige | -518 | Générique | 89.2671 | 187.445
4294966777 | Rez-de-Jardin | Beige | -519 | Générique | 89.2675 | 187.445
4294966776 | Rez-de-Jardin | Beige | -520 | Générique | 89.2674 | 187.445
4294966775 | Rez-de-Jardin | Noyer 01 | -521 | Dormant | 7608 | 6388
4294966774 | Rez-de-Jardin | Noyer 01 | -522 | Dormant | 10591.6 | 7133.24
4294966773 | Rez-de-Jardin | Noyer 01 | -523 | Générique | 267.609 | 446.71
4294966772 | Rez-de-Jardin | Noyer 01 | -524 | Générique | 1011.18 | 1382.89
4294966771 | Rez-de-Jardin | Noyer 01 | -525 | Générique | 1011.19 | 1382.9
4294966770 | Rez-de-Jardin | Noyer 01 | -526 | Générique | 1011.18 | 1382.9
4294966769 | Rez-de-Jardin | Noyer 01 | -527 | Générique | 1011.18 | 1382.89
4294966768 | Rez-de-Jardin | Noyer 01 | -528 | Générique | 1011.18 | 1382.89
4294966767 | Rez-de-Jardin | Noyer 01 | -529 | Générique | 564.067 | 777.571
4294966766 | Rez-de-Jardin | Noyer 01 | -530 | Générique | 554.742 | 764.945
4294966765 | Rez-de-Jardin | Noyer 01 | -531 | Générique | 545.416 | 752.32
4294966764 | Rez-de-Jardin | Noyer 01 | -532 | Générique | 536.091 | 739.694
4294966763 | Rez-de-Jardin | Noyer 01 | -533 | Générique | 526.765 | 727.068
4294966762 | Rez-de-Jardin | Noyer 01 | -534 | Générique | 517.44 | 714.443
4294966761 | Rez-de-Jardin | Noyer 01 | -535 | Générique | 508.115 | 701.817
4294966760 | Rez-de-Jardin | Noyer 01 | -536 | Générique | 498.79 | 689.192
4294966759 | Rez-de-Jardin | Noyer 01 | -537 | Générique | 489.463 | 676.565
4294966758 | Rez-de-Jardin | Noyer 01 | -538 | Générique | 480.138 | 663.94
4294966757 | Rez-de-Jardin | Noyer 01 | -539 | Dormant | 5256 | 3576
4294966755 | Rez-de-Jardin | Aluminium satiné | -541 | Dormant | 1728 | 2592
4294966754 | Rez-de-Jardin | Aluminium satiné | -542 | Générique | 10.894 | 30.8305
4294966753 | Rez-de-Jardin | Aluminium satiné | -543 | Générique | 43.5321 | 97.1136
4294966752 | Rez-de-Jardin | Aluminium satiné | -544 | Générique | 43.5321 | 97.1136
4294966751 | Rez-de-Jardin | Aluminium satiné | -545 | Générique | 43.5321 | 97.1136
4294966750 | Rez-de-Jardin | Aluminium satiné | -546 | Générique | 43.5321 | 97.1136
4294966749 | Rez-de-Jardin | Aluminium satiné | -547 | Générique | 43.532 | 97.1136
4294966748 | Rez-de-Jardin | Aluminium satiné | -548 | Générique | 43.5321 | 97.1136
4294966747 | Rez-de-Jardin | Aluminium satiné | -549 | Générique | 10.894 | 30.8305
4294966746 | Rez-de-Jardin | Aluminium satiné | -550 | Générique | 10.894 | 30.8305
4294966745 | Rez-de-Jardin | Aluminium satiné | -551 | Générique | 43.532 | 97.1136
4294966744 | Rez-de-Jardin | Aluminium satiné | -552 | Générique | 43.5321 | 97.1136
4294966743 | Rez-de-Jardin | Aluminium satiné | -553 | Générique | 43.5321 | 97.1136
4294966742 | Rez-de-Jardin | Aluminium satiné | -554 | Générique | 43.5321 | 97.1136
4294966741 | Rez-de-Jardin | Aluminium satiné | -555 | Générique | 43.5321 | 97.1136
4294966740 | Rez-de-Jardin | Aluminium satiné | -556 | Générique | 43.5321 | 97.1136
4294966739 | Rez-de-Jardin | Aluminium satiné | -557 | Générique | 10.894 | 30.8305
4294966738 | Rez-de-Jardin | Acier | -558 | Dormant | 1530.21 | 2295.31
4294966737 | Rez-de-Jardin | Acier | -559 | Générique | 30.8435 | 127.807
4294966736 | Rez-de-Jardin | Acier | -560 | Générique | 48.3755 | 196.098
4294966735 | Rez-de-Jardin | Acier | -561 | Générique | 56.8024 | 229.374
4294966734 | Rez-de-Jardin | Acier | -562 | Générique | 60.5288 | 244.132
4294966733 | Rez-de-Jardin | Acier | -563 | Générique | 60.5289 | 244.132
4294966732 | Rez-de-Jardin | Acier | -564 | Générique | 56.8023 | 229.374
4294966731 | Rez-de-Jardin | Acier | -565 | Générique | 48.3755 | 196.098
4294966730 | Rez-de-Jardin | Acier | -566 | Générique | 30.8433 | 127.806
4294966729 | Rez-de-Jardin | Acier | -567 | Générique | 68.5263 | 197.159
4294966728 | Rez-de-Jardin | Acier | -568 | Générique | 124.555 | 340.082
4294966727 | Rez-de-Jardin | Acier | -569 | Générique | 151.01 | 409.239
4294966726 | Rez-de-Jardin | Acier | -570 | Générique | 164.608 | 445.097
4294966725 | Rez-de-Jardin | Acier | -571 | Générique | 169.144 | 457.049
4294966724 | Rez-de-Jardin | Acier | -572 | Générique | 164.608 | 445.097
4294966723 | Rez-de-Jardin | Acier | -573 | Générique | 151.01 | 409.239
4294966722 | Rez-de-Jardin | Acier | -574 | Générique | 124.555 | 340.082
4294966721 | Rez-de-Jardin | Acier | -575 | Générique | 68.5262 | 197.159
4294966720 | Rez-de-Jardin | Acier | -576 | Dormant | 1530.21 | 2295.31
4294966719 | Rez-de-Jardin | Acier | -577 | Générique | 30.8435 | 127.807
4294966718 | Rez-de-Jardin | Acier | -578 | Générique | 48.3755 | 196.098
4294966717 | Rez-de-Jardin | Acier | -579 | Générique | 56.8024 | 229.374
4294966716 | Rez-de-Jardin | Acier | -580 | Générique | 60.5288 | 244.132
4294966715 | Rez-de-Jardin | Acier | -581 | Générique | 60.5289 | 244.132
4294966714 | Rez-de-Jardin | Acier | -582 | Générique | 56.8023 | 229.374
4294966713 | Rez-de-Jardin | Acier | -583 | Générique | 48.3755 | 196.098
4294966712 | Rez-de-Jardin | Acier | -584 | Générique | 30.8433 | 127.806
4294966711 | Rez-de-Jardin | Acier | -585 | Générique | 68.5263 | 197.159
4294966710 | Rez-de-Jardin | Acier | -586 | Générique | 124.555 | 340.082
4294966709 | Rez-de-Jardin | Acier | -587 | Générique | 151.01 | 409.239
4294966708 | Rez-de-Jardin | Acier | -588 | Générique | 164.608 | 445.097
4294966707 | Rez-de-Jardin | Acier | -589 | Générique | 169.144 | 457.049
4294966706 | Rez-de-Jardin | Acier | -590 | Générique | 164.608 | 445.097
4294966705 | Rez-de-Jardin | Acier | -591 | Générique | 151.01 | 409.239
4294966704 | Rez-de-Jardin | Acier | -592 | Générique | 124.555 | 340.082
4294966703 | Rez-de-Jardin | Acier | -593 | Générique | 68.5262 | 197.159
4294966702 | Rez-de-Jardin | Aluminium satiné | -594 | Dormant | 1536 | 2304
4294966701 | Rez-de-Jardin | Aluminium satiné | -595 | Générique | 15.5566 | 40.2996
4294966700 | Rez-de-Jardin | Aluminium satiné | -596 | Générique | 77.1202 | 165.326
4294966699 | Rez-de-Jardin | Aluminium satiné | -597 | Générique | 138.684 | 290.353
4294966698 | Rez-de-Jardin | Aluminium satiné | -598 | Générique | 200.247 | 415.38
4294966697 | Rez-de-Jardin | Aluminium satiné | -599 | Générique | 138.684 | 290.353
4294966696 | Rez-de-Jardin | Aluminium satiné | -600 | Générique | 77.1202 | 165.326
4294966695 | Rez-de-Jardin | Aluminium satiné | -601 | Générique | 15.5566 | 40.2996
4294966694 | Rez-de-Jardin | Aluminium satiné | -602 | Générique | 15.5566 | 40.2996
4294966693 | Rez-de-Jardin | Aluminium satiné | -603 | Générique | 77.1202 | 165.326
4294966692 | Rez-de-Jardin | Aluminium satiné | -604 | Générique | 138.684 | 290.353
4294966691 | Rez-de-Jardin | Aluminium satiné | -605 | Générique | 200.247 | 415.38
4294966690 | Rez-de-Jardin | Aluminium satiné | -606 | Générique | 138.684 | 290.353
4294966689 | Rez-de-Jardin | Aluminium satiné | -607 | Générique | 77.1202 | 165.326
4294966688 | Rez-de-Jardin | Aluminium satiné | -608 | Générique | 15.5566 | 40.2996
4294966687 | Rez-de-Jardin | Aluminium satiné | -609 | Dormant | 1536 | 2304
4294966686 | Rez-de-Jardin | Aluminium satiné | -610 | Générique | 15.5566 | 40.2996
4294966685 | Rez-de-Jardin | Aluminium satiné | -611 | Générique | 77.1202 | 165.326
4294966684 | Rez-de-Jardin | Aluminium satiné | -612 | Générique | 138.684 | 290.353
4294966683 | Rez-de-Jardin | Aluminium satiné | -613 | Générique | 200.247 | 415.38
4294966682 | Rez-de-Jardin | Aluminium satiné | -614 | Générique | 138.684 | 290.353
4294966681 | Rez-de-Jardin | Aluminium satiné | -615 | Générique | 77.1202 | 165.326
4294966680 | Rez-de-Jardin | Aluminium satiné | -616 | Générique | 15.5566 | 40.2996
4294966679 | Rez-de-Jardin | Aluminium satiné | -617 | Générique | 15.5566 | 40.2996
4294966678 | Rez-de-Jardin | Aluminium satiné | -618 | Générique | 77.1202 | 165.326
4294966677 | Rez-de-Jardin | Aluminium satiné | -619 | Générique | 138.684 | 290.353
4294966676 | Rez-de-Jardin | Aluminium satiné | -620 | Générique | 200.247 | 415.38
4294966675 | Rez-de-Jardin | Aluminium satiné | -621 | Générique | 138.684 | 290.353
4294966674 | Rez-de-Jardin | Aluminium satiné | -622 | Générique | 77.1202 | 165.326
4294966673 | Rez-de-Jardin | Aluminium satiné | -623 | Générique | 15.5566 | 40.2996
4294967268 | Rez-de-chaussée | Noyer 01 | -28 | Élément Escalier | 507668 | 128491
4294967153 | Rez-de-chaussée | Aluminium satiné | -143 | Dormant | 3072 | 4608
4294967152 | Rez-de-chaussée | Aluminium satiné | -144 | Générique | 489.431 | 1000.12
4294967151 | Rez-de-chaussée | Aluminium satiné | -145 | Générique | 489.431 | 1000.12
4294967150 | Rez-de-chaussée | Aluminium satiné | -146 | Générique | 489.431 | 1000.12
4294967149 | Rez-de-chaussée | Aluminium satiné | -147 | Générique | 89.2673 | 187.445
4294967148 | Rez-de-chaussée | Aluminium satiné | -148 | Générique | 89.2672 | 187.445
4294967147 | Rez-de-chaussée | Aluminium satiné | -149 | Générique | 89.2673 | 187.445
4294967146 | Rez-de-chaussée | Aluminium satiné | -150 | Générique | 89.2673 | 187.445
4294967145 | Rez-de-chaussée | Aluminium satiné | -151 | Générique | 89.2673 | 187.445
4294967144 | Rez-de-chaussée | Aluminium satiné | -152 | Générique | 89.2672 | 187.445
4294967143 | Rez-de-chaussée | Aluminium satiné | -153 | Générique | 89.2674 | 187.445
4294967142 | Rez-de-chaussée | Aluminium satiné | -154 | Générique | 89.2673 | 187.445
4294967141 | Rez-de-chaussée | Aluminium satiné | -155 | Générique | 89.2672 | 187.445
4294967140 | Rez-de-chaussée | Aluminium satiné | -156 | Générique | 89.2674 | 187.445
4294967139 | Rez-de-chaussée | Aluminium satiné | -157 | Générique | 89.2677 | 187.445
4294967138 | Rez-de-chaussée | Aluminium satiné | -158 | Générique | 89.2671 | 187.445
4294967137 | Rez-de-chaussée | Aluminium satiné | -159 | Générique | 89.2673 | 187.445
4294967136 | Rez-de-chaussée | Aluminium satiné | -160 | Générique | 89.2674 | 187.445
4294967135 | Rez-de-chaussée | Aluminium satiné | -161 | Générique | 89.2672 | 187.445
4294967134 | Rez-de-chaussée | Aluminium satiné | -162 | Générique | 89.2677 | 187.445
4294967115 | Rez-de-chaussée | Aluminium satiné | -181 | Dormant | 2784 | 4176
4294967114 | Rez-de-chaussée | Aluminium satiné | -182 | Générique | 434.024 | 887.594
4294967113 | Rez-de-chaussée | Aluminium satiné | -183 | Générique | 434.023 | 887.594
4294967112 | Rez-de-chaussée | Aluminium satiné | -184 | Générique | 434.024 | 887.594
4294967111 | Rez-de-chaussée | Aluminium satiné | -185 | Générique | 89.2673 | 187.445
4294967110 | Rez-de-chaussée | Aluminium satiné | -186 | Générique | 89.2673 | 187.445
4294967109 | Rez-de-chaussée | Aluminium satiné | -187 | Générique | 89.2673 | 187.445
4294967108 | Rez-de-chaussée | Aluminium satiné | -188 | Générique | 89.2673 | 187.445
4294967107 | Rez-de-chaussée | Aluminium satiné | -189 | Générique | 89.2673 | 187.445
4294967106 | Rez-de-chaussée | Aluminium satiné | -190 | Générique | 89.2672 | 187.445
4294967105 | Rez-de-chaussée | Aluminium satiné | -191 | Générique | 89.2672 | 187.445
4294967104 | Rez-de-chaussée | Aluminium satiné | -192 | Générique | 89.2674 | 187.445
4294967103 | Rez-de-chaussée | Aluminium satiné | -193 | Générique | 89.2672 | 187.445
4294967102 | Rez-de-chaussée | Aluminium satiné | -194 | Générique | 89.2673 | 187.445
4294967101 | Rez-de-chaussée | Aluminium satiné | -195 | Générique | 89.2674 | 187.445
4294967100 | Rez-de-chaussée | Aluminium satiné | -196 | Générique | 89.2673 | 187.445
4294967099 | Rez-de-chaussée | Aluminium satiné | -197 | Générique | 89.2671 | 187.445
4294967098 | Rez-de-chaussée | Aluminium satiné | -198 | Générique | 89.2671 | 187.445
4294967097 | Rez-de-chaussée | Aluminium satiné | -199 | Dormant | 2736 | 4104
4294967096 | Rez-de-chaussée | Aluminium satiné | -200 | Générique | 424.789 | 868.84
4294967095 | Rez-de-chaussée | Aluminium satiné | -201 | Générique | 424.789 | 868.84
4294967094 | Rez-de-chaussée | Aluminium satiné | -202 | Générique | 424.789 | 868.841
4294967093 | Rez-de-chaussée | Aluminium satiné | -203 | Générique | 89.2673 | 187.445
4294967092 | Rez-de-chaussée | Aluminium satiné | -204 | Générique | 89.2672 | 187.445
4294967091 | Rez-de-chaussée | Aluminium satiné | -205 | Générique | 89.2673 | 187.445
4294967090 | Rez-de-chaussée | Aluminium satiné | -206 | Générique | 89.2673 | 187.445
4294967089 | Rez-de-chaussée | Aluminium satiné | -207 | Générique | 89.2673 | 187.445
4294967088 | Rez-de-chaussée | Aluminium satiné | -208 | Générique | 89.2672 | 187.445
4294967087 | Rez-de-chaussée | Aluminium satiné | -209 | Générique | 89.2673 | 187.445
4294967086 | Rez-de-chaussée | Aluminium satiné | -210 | Générique | 89.2672 | 187.445
4294967085 | Rez-de-chaussée | Aluminium satiné | -211 | Générique | 89.2673 | 187.445
4294967084 | Rez-de-chaussée | Aluminium satiné | -212 | Générique | 89.2674 | 187.445
4294967083 | Rez-de-chaussée | Aluminium satiné | -213 | Générique | 89.2678 | 187.445
4294967082 | Rez-de-chaussée | Aluminium satiné | -214 | Générique | 89.2673 | 187.445
4294967081 | Rez-de-chaussée | Aluminium satiné | -215 | Générique | 89.2671 | 187.445
4294967080 | Rez-de-chaussée | Aluminium satiné | -216 | Générique | 89.2673 | 187.445
4294967273 | Niveau 1 | Noyer 01 | -23 | Élément Escalier | 13012.5 | 110508
4294967079 | Niveau 1 | Aluminium satiné | -217 | Dormant | 2784 | 4176
4294967078 | Niveau 1 | Aluminium satiné | -218 | Générique | 434.024 | 887.594
4294967077 | Niveau 1 | Aluminium satiné | -219 | Générique | 434.023 | 887.594
4294967076 | Niveau 1 | Aluminium satiné | -220 | Générique | 434.024 | 887.594
4294967075 | Niveau 1 | Aluminium satiné | -221 | Générique | 89.2673 | 187.445
4294967074 | Niveau 1 | Aluminium satiné | -222 | Générique | 89.2673 | 187.445
4294967073 | Niveau 1 | Aluminium satiné | -223 | Générique | 89.2673 | 187.445
4294967072 | Niveau 1 | Aluminium satiné | -224 | Générique | 89.2673 | 187.445
4294967071 | Niveau 1 | Aluminium satiné | -225 | Générique | 89.2673 | 187.445
4294967070 | Niveau 1 | Aluminium satiné | -226 | Générique | 89.2672 | 187.445
4294967069 | Niveau 1 | Aluminium satiné | -227 | Générique | 89.2672 | 187.445
4294967068 | Niveau 1 | Aluminium satiné | -228 | Générique | 89.2674 | 187.445
4294967067 | Niveau 1 | Aluminium satiné | -229 | Générique | 89.2672 | 187.445
4294967066 | Niveau 1 | Aluminium satiné | -230 | Générique | 89.2673 | 187.445
4294967065 | Niveau 1 | Aluminium satiné | -231 | Générique | 89.2674 | 187.445
4294967064 | Niveau 1 | Aluminium satiné | -232 | Générique | 89.2673 | 187.445
4294967063 | Niveau 1 | Aluminium satiné | -233 | Générique | 89.2671 | 187.445
4294967062 | Niveau 1 | Aluminium satiné | -234 | Générique | 89.2671 | 187.445
4294967061 | Niveau 1 | Aluminium satiné | -235 | Dormant | 2784 | 4176
4294967060 | Niveau 1 | Aluminium satiné | -236 | Générique | 434.024 | 887.594
4294967059 | Niveau 1 | Aluminium satiné | -237 | Générique | 434.023 | 887.594
4294967058 | Niveau 1 | Aluminium satiné | -238 | Générique | 434.024 | 887.594
4294967057 | Niveau 1 | Aluminium satiné | -239 | Générique | 89.2673 | 187.445
4294967056 | Niveau 1 | Aluminium satiné | -240 | Générique | 89.2673 | 187.445
4294967055 | Niveau 1 | Aluminium satiné | -241 | Générique | 89.2673 | 187.445
4294967054 | Niveau 1 | Aluminium satiné | -242 | Générique | 89.2673 | 187.445
4294967053 | Niveau 1 | Aluminium satiné | -243 | Générique | 89.2673 | 187.445
4294967052 | Niveau 1 | Aluminium satiné | -244 | Générique | 89.2672 | 187.445
4294967051 | Niveau 1 | Aluminium satiné | -245 | Générique | 89.2672 | 187.445
4294967050 | Niveau 1 | Aluminium satiné | -246 | Générique | 89.2674 | 187.445
4294967049 | Niveau 1 | Aluminium satiné | -247 | Générique | 89.2672 | 187.445
4294967048 | Niveau 1 | Aluminium satiné | -248 | Générique | 89.2673 | 187.445
4294967047 | Niveau 1 | Aluminium satiné | -249 | Générique | 89.2674 | 187.445
4294967046 | Niveau 1 | Aluminium satiné | -250 | Générique | 89.2673 | 187.445
4294967045 | Niveau 1 | Aluminium satiné | -251 | Générique | 89.2671 | 187.445
4294967044 | Niveau 1 | Aluminium satiné | -252 | Générique | 89.2671 | 187.445
4294967043 | Niveau 1 | Aluminium satiné | -253 | Dormant | 3072 | 4608
4294967042 | Niveau 1 | Aluminium satiné | -254 | Générique | 489.431 | 1000.12
4294967041 | Niveau 1 | Aluminium satiné | -255 | Générique | 489.431 | 1000.12
4294967040 | Niveau 1 | Aluminium satiné | -256 | Générique | 489.431 | 1000.12
4294967039 | Niveau 1 | Aluminium satiné | -257 | Générique | 89.2673 | 187.445
4294967038 | Niveau 1 | Aluminium satiné | -258 | Générique | 89.2672 | 187.445
4294967037 | Niveau 1 | Aluminium satiné | -259 | Générique | 89.2673 | 187.445
4294967036 | Niveau 1 | Aluminium satiné | -260 | Générique | 89.2673 | 187.445
4294967035 | Niveau 1 | Aluminium satiné | -261 | Générique | 89.2673 | 187.445
4294967034 | Niveau 1 | Aluminium satiné | -262 | Générique | 89.2672 | 187.445
4294967033 | Niveau 1 | Aluminium satiné | -263 | Générique | 89.2674 | 187.445
4294967032 | Niveau 1 | Aluminium satiné | -264 | Générique | 89.2673 | 187.445
4294967031 | Niveau 1 | Aluminium satiné | -265 | Générique | 89.2672 | 187.445
4294967030 | Niveau 1 | Aluminium satiné | -266 | Générique | 89.2674 | 187.445
4294967029 | Niveau 1 | Aluminium satiné | -267 | Générique | 89.2677 | 187.445
4294967028 | Niveau 1 | Aluminium satiné | -268 | Générique | 89.2671 | 187.445
4294967027 | Niveau 1 | Aluminium satiné | -269 | Générique | 89.2673 | 187.445
4294967026 | Niveau 1 | Aluminium satiné | -270 | Générique | 89.2674 | 187.445
4294967025 | Niveau 1 | Aluminium satiné | -271 | Générique | 89.2672 | 187.445
4294967024 | Niveau 1 | Aluminium satiné | -272 | Générique | 89.2677 | 187.445
4294967193 | Niveau 2 | Aluminium satiné | -103 | Dormant | 3072 | 4608
4294967192 | Niveau 2 | Aluminium satiné | -104 | Générique | 489.431 | 1000.12
4294967191 | Niveau 2 | Aluminium satiné | -105 | Générique | 489.431 | 1000.12
4294967190 | Niveau 2 | Aluminium satiné | -106 | Générique | 489.431 | 1000.12
4294967189 | Niveau 2 | Aluminium satiné | -107 | Générique | 89.2673 | 187.445
4294967188 | Niveau 2 | Aluminium satiné | -108 | Générique | 89.2672 | 187.445
4294967187 | Niveau 2 | Aluminium satiné | -109 | Générique | 89.2673 | 187.445
4294967186 | Niveau 2 | Aluminium satiné | -110 | Générique | 89.2673 | 187.445
4294967185 | Niveau 2 | Aluminium satiné | -111 | Générique | 89.2673 | 187.445
4294967184 | Niveau 2 | Aluminium satiné | -112 | Générique | 89.2672 | 187.445
4294967183 | Niveau 2 | Aluminium satiné | -113 | Générique | 89.2674 | 187.445
4294967182 | Niveau 2 | Aluminium satiné | -114 | Générique | 89.2673 | 187.445
4294967181 | Niveau 2 | Aluminium satiné | -115 | Générique | 89.2672 | 187.445
4294967180 | Niveau 2 | Aluminium satiné | -116 | Générique | 89.2674 | 187.445
4294967179 | Niveau 2 | Aluminium satiné | -117 | Générique | 89.2677 | 187.445
4294967178 | Niveau 2 | Aluminium satiné | -118 | Générique | 89.2671 | 187.445
4294967177 | Niveau 2 | Aluminium satiné | -119 | Générique | 89.2673 | 187.445
4294967176 | Niveau 2 | Aluminium satiné | -120 | Générique | 89.2674 | 187.445
4294967175 | Niveau 2 | Aluminium satiné | -121 | Générique | 89.2672 | 187.445
4294967174 | Niveau 2 | Aluminium satiné | -122 | Générique | 89.2677 | 187.445
4294967173 | Niveau 2 | Aluminium satiné | -123 | Dormant | 2784 | 4176
4294967172 | Niveau 2 | Aluminium satiné | -124 | Générique | 434.024 | 887.594
4294967171 | Niveau 2 | Aluminium satiné | -125 | Générique | 434.023 | 887.594
4294967170 | Niveau 2 | Aluminium satiné | -126 | Générique | 434.024 | 887.594
4294967169 | Niveau 2 | Aluminium satiné | -127 | Générique | 89.2673 | 187.445
4294967168 | Niveau 2 | Aluminium satiné | -128 | Générique | 89.2673 | 187.445
4294967167 | Niveau 2 | Aluminium satiné | -129 | Générique | 89.2673 | 187.445
4294967166 | Niveau 2 | Aluminium satiné | -130 | Générique | 89.2673 | 187.445
4294967165 | Niveau 2 | Aluminium satiné | -131 | Générique | 89.2673 | 187.445
4294967164 | Niveau 2 | Aluminium satiné | -132 | Générique | 89.2672 | 187.445
4294967163 | Niveau 2 | Aluminium satiné | -133 | Générique | 89.2672 | 187.445
4294967162 | Niveau 2 | Aluminium satiné | -134 | Générique | 89.2674 | 187.445
4294967161 | Niveau 2 | Aluminium satiné | -135 | Générique | 89.2672 | 187.445
4294967160 | Niveau 2 | Aluminium satiné | -136 | Générique | 89.2673 | 187.445
4294967159 | Niveau 2 | Aluminium satiné | -137 | Générique | 89.2674 | 187.445
4294967158 | Niveau 2 | Aluminium satiné | -138 | Générique | 89.2673 | 187.445
4294967157 | Niveau 2 | Aluminium satiné | -139 | Générique | 89.2671 | 187.445
4294967156 | Niveau 2 | Aluminium satiné | -140 | Générique | 89.2671 | 187.445
4294967133 | Niveau 2 | Aluminium satiné | -163 | Dormant | 2784 | 4176
4294967132 | Niveau 2 | Aluminium satiné | -164 | Générique | 434.024 | 887.594
4294967131 | Niveau 2 | Aluminium satiné | -165 | Générique | 434.023 | 887.594
4294967130 | Niveau 2 | Aluminium satiné | -166 | Générique | 434.024 | 887.594
4294967129 | Niveau 2 | Aluminium satiné | -167 | Générique | 89.2673 | 187.445
4294967128 | Niveau 2 | Aluminium satiné | -168 | Générique | 89.2673 | 187.445
4294967127 | Niveau 2 | Aluminium satiné | -169 | Générique | 89.2673 | 187.445
4294967126 | Niveau 2 | Aluminium satiné | -170 | Générique | 89.2673 | 187.445
4294967125 | Niveau 2 | Aluminium satiné | -171 | Générique | 89.2673 | 187.445
4294967124 | Niveau 2 | Aluminium satiné | -172 | Générique | 89.2672 | 187.445
4294967123 | Niveau 2 | Aluminium satiné | -173 | Générique | 89.2672 | 187.445
4294967122 | Niveau 2 | Aluminium satiné | -174 | Générique | 89.2674 | 187.445
4294967121 | Niveau 2 | Aluminium satiné | -175 | Générique | 89.2672 | 187.445
4294967120 | Niveau 2 | Aluminium satiné | -176 | Générique | 89.2673 | 187.445
4294967119 | Niveau 2 | Aluminium satiné | -177 | Générique | 89.2674 | 187.445
4294967118 | Niveau 2 | Aluminium satiné | -178 | Générique | 89.2673 | 187.445
4294967117 | Niveau 2 | Aluminium satiné | -179 | Générique | 89.2671 | 187.445
4294967116 | Niveau 2 | Aluminium satiné | -180 | Générique | 89.2671 | 187.445
4294967252 | Mezzanine | Blanc trafic | -44 | Dormant | 2784 | 4176
4294967251 | Mezzanine | Blanc trafic | -45 | Générique | 434.024 | 887.594
4294967250 | Mezzanine | Blanc trafic | -46 | Générique | 434.023 | 887.594
4294967249 | Mezzanine | Blanc trafic | -47 | Générique | 434.024 | 887.594
4294967248 | Mezzanine | Blanc trafic | -48 | Générique | 89.2673 | 187.445
4294967247 | Mezzanine | Blanc trafic | -49 | Générique | 89.2673 | 187.445
4294967246 | Mezzanine | Blanc trafic | -50 | Générique | 89.2673 | 187.445
4294967245 | Mezzanine | Blanc trafic | -51 | Générique | 89.2673 | 187.445
4294967244 | Mezzanine | Blanc trafic | -52 | Générique | 89.2673 | 187.445
4294967243 | Mezzanine | Blanc trafic | -53 | Générique | 89.2672 | 187.445
4294967242 | Mezzanine | Blanc trafic | -54 | Générique | 89.2672 | 187.445
4294967241 | Mezzanine | Blanc trafic | -55 | Générique | 89.2674 | 187.445
4294967240 | Mezzanine | Blanc trafic | -56 | Générique | 89.2672 | 187.445
4294967239 | Mezzanine | Blanc trafic | -57 | Générique | 89.2673 | 187.445
4294967238 | Mezzanine | Blanc trafic | -58 | Générique | 89.2674 | 187.445
4294967237 | Mezzanine | Blanc trafic | -59 | Générique | 89.2673 | 187.445
4294967236 | Mezzanine | Blanc trafic | -60 | Générique | 89.2671 | 187.445
4294967235 | Mezzanine | Blanc trafic | -61 | Générique | 89.2671 | 187.445
4294967228 | Mezzanine | Blanc trafic | -68 | Dormant | 2512 | 3768
4294967227 | Mezzanine | Blanc trafic | -69 | Générique | 381.695 | 781.322
4294967226 | Mezzanine | Blanc trafic | -70 | Générique | 381.694 | 781.322
4294967225 | Mezzanine | Blanc trafic | -71 | Générique | 381.695 | 781.322
4294967224 | Mezzanine | Blanc trafic | -72 | Générique | 89.2673 | 187.445
4294967223 | Mezzanine | Blanc trafic | -73 | Générique | 89.2673 | 187.445
4294967222 | Mezzanine | Blanc trafic | -74 | Générique | 89.2672 | 187.445
4294967221 | Mezzanine | Blanc trafic | -75 | Générique | 89.2672 | 187.445
4294967220 | Mezzanine | Blanc trafic | -76 | Générique | 89.2672 | 187.445
4294967219 | Mezzanine | Blanc trafic | -77 | Générique | 89.2674 | 187.445
4294967218 | Mezzanine | Blanc trafic | -78 | Générique | 89.2673 | 187.445
4294967217 | Mezzanine | Blanc trafic | -79 | Générique | 89.2672 | 187.445
4294967216 | Mezzanine | Blanc trafic | -80 | Générique | 89.2673 | 187.445
4294967215 | Mezzanine | Blanc trafic | -81 | Générique | 89.2671 | 187.445
4294967214 | Mezzanine | Blanc trafic | -82 | Générique | 89.2671 | 187.445
4294967213 | Mezzanine | Blanc trafic | -83 | Générique | 89.2672 | 187.445
4294967212 | Mezzanine | Blanc trafic | -84 | Générique | 89.2672 | 187.445
4294967211 | Couverture | Acier | -85 | Dormant | 1256 | 2512
4294967209 | Couverture | Acier | -87 | Dormant | 1256 | 2512
4294967207 | Couverture | Acier | -89 | Dormant | 1336 | 2672
4294967205 | Couverture | Acier | -91 | Dormant | 1256 | 2512
4294967203 | Couverture | Acier | -93 | Dormant | 1296 | 2592
4294967201 | Couverture | Acier | -95 | Dormant | 1784 | 3568
4294967199 | Couverture | Acier | -97 | Dormant | 1776 | 3552
4294967197 | Couverture | Acier | -99 | Dormant | 1256 | 2512
4294967195 | Couverture | Acier | -101 | Dormant | 1256 | 2512
4294967019 | Couverture | Acier inoxydable opaque | -277 | Dormant | 8942.65 | 7452.21
4294967018 | Couverture | Acier inoxydable opaque | -278 | Dormant | 8197.97 | 6813.82
4294967016 | Couverture | Acier inoxydable opaque | -280 | Dormant | 7422.64 | 6185.54
4294967015 | Couverture | Acier inoxydable opaque | -281 | Dormant | 6687.11 | 5572.59
4294967013 | Couverture | Acier inoxydable opaque | -283 | Dormant | 7422.64 | 6185.54
4294967012 | Couverture | Acier inoxydable opaque | -284 | Dormant | 6687.11 | 5572.59
4294967010 | Couverture | Acier inoxydable opaque | -286 | Dormant | 8942.65 | 7452.21
4294967009 | Couverture | Acier inoxydable opaque | -287 | Dormant | 8197.97 | 6813.82
4294967007 | Couverture | Acier inoxydable opaque | -289 | Dormant | 12752 | 10626.7
4294967006 | Couverture | Acier inoxydable opaque | -290 | Dormant | 12033.5 | 10028
4294967004 | Couverture | Acier | -292 | Dormant | 1336 | 2672
4294966906 | Couverture | Acier | -390 | Dormant | 1256 | 2512
4294966904 | Couverture | Acier | -392 | Dormant | 1256 | 2512
4294966672 | Couverture | Acier | -624 | Dormant | 1248 | 2496
4294966670 | Couverture | Acier | -626 | Dormant | 1248 | 2496
4294966668 | Couverture | Acier | -628 | Dormant | 1312 | 2624
4294966666 | Couverture | Acier | -630 | Dormant | 1312 | 2624
4294966664 | Couverture | Acier | -632 | Dormant | 1336 | 2672
4294966662 | Couverture | Acier | -634 | Dormant | 1312 | 2624
4294966660 | Couverture | Acier | -636 | Dormant | 1312 | 2624
4294966658 | Couverture | Acier | -638 | Dormant | 848 | 1696
4294966656 | Couverture | Acier | -640 | Dormant | 960 | 1920
4294966654 | Couverture | Acier | -642 | Dormant | 848 | 1696
4294966652 | Couverture | Acier | -644 | Dormant | 1232 | 2464
4294966650 | Couverture | Acier | -646 | Dormant | 1192 | 2384
4294966648 | Couverture | Acier | -648 | Dormant | 1256 | 2512
4294966646 | Couverture | Acier | -650 | Dormant | 1192 | 2384
4294966644 | Couverture | Acier | -652 | Dormant | 960 | 1920
4294966642 | Couverture | Acier | -654 | Dormant | 1256 | 2512
4294966640 | Couverture | Acier | -656 | Dormant | 1232 | 2464

# IfcOpeningElement: Opening (367)
CTLG_EXTERNAL_LINK - 0, DocType: 2; 0, Tag: 0
IFC_PSET_PolygonOffset - polygonOffsetFactor: 2; polygonOffsetUnits: 2
Name | In | __RECOGNIZE__, ID | TPLG | TPLG_OD | GENERATE | 0, Crc
4294966388_11 | Rez-de-Jardin | -908 | 2002 | 2002 | 0 | -1292786862
4294966387_11 | Rez-de-Jardin | -909 | 2002 | 2002 | 0 | -1292786862
4294966513_11 | Rez-de-Jardin | -783 | 2002 | 2002 | 0 | -1292786862
4294966498_17 | Rez-de-Jardin | -798 | 2002 | 2002 | 0 | -1292786862
4294966516_11 | Rez-de-Jardin | -780 | 2002 | 2002 | 0 | -1292786862
4294966514_11 | Rez-de-Jardin | -782 | 2002 | 2002 | 0 | -1292786862
4294966517_11 | Rez-de-Jardin | -779 | 2002 | 2002 | 0 | -1292786862
4294966497_17 | Rez-de-Jardin | -799 | 2002 | 2002 | 0 | -1292786862
Baie 577816 | Rez-de-Jardin | 577816 | 114 | 9006 | 1 | -746779066 | Description: _VTO_Baie; CTLG_EXTERNAL_LINK - 1, DocType: 9; 1, Tag: 211; 1, Crc: -732809594; IFC_Pset_Caractéristiques - ID: 577816; Numérotation: 134; Numéro niveau: 02; Titre niveau: Rez-de-Jardin; IFC_Pset_Géométrie_Allège - Hauteur: 0 cm; Stratigraphie: ...; Épaisseur: 0 cm; IFC_Pset_Géométrie_Ébrasement - Présent: no; Côté supérieur: no; Côté INFÉRIEUR: no; Épaisseur extérieure: 0 cm; Épaisseur latérale gauche: 0 cm; Épaisseur latérale droite: 0 cm; Épiasseur latérale supérieure: 0 cm; Épaisseur diagonale gauche: 0 cm; Épaisseur diagonale droite: 0 cm; Épaisseur diagonale inférieure: 0 cm; Épaisseur diagonale supérieure: 0 cm; Épaisseur intérieur: 0 cm; IFC_Pset_Géométrie_Seuil - Type: Aucun; Épaisseur: 0 cm; Épaisseur interne: 0 cm; Décalage séparation: 0 cm; Appui extérieur: 0 cm; Appui intérieur: 0 cm; Côté latéral externe: 0 cm; Côté latéral interne: 0 cm; IFC_Pset_Géométrie_Chambranle - Position: Aucun; Épaisseur Chambranle intérieur: 0 cm; Longueur Chambranle intérieur: 0 cm; Superposition Chambranle intérieur: 0 cm; Épaisseur Intrados: 0 cm; Épaisseur Chambranle extérieur: 0 cm; Largeur Chambranle extérieur: 0 cm; Superposition Chambranle extérieur: 0 cm; Épaisseur Intrados extérieur: 0 cm; Décalage séparation intrados: 0 cm; IFC_Pset_Géométrie_CORNICHE depuis profil - Position: Aucune; sets with these values: 2; IFC_Pset_Géométrie_CORNICHE Extérieure à partir d'un profil - Décalage: 0; Angle: 0 deg; Symétrie: no; Fermer: no; sets with these values: 2; IFC_Pset_Géométrie_BASE Extérieure à partir d'un profil - Angle: 0 deg; Symétrie: no; Côté: 0 cm; sets with these values: 2; IFC_Pset_Géométrie - Côté extérieur: 0; Invertir (dte/gche): no; Invertir (intérieur/extérieur): no; Forme: Rectangle; Largeur: 178.993 cm; Hauteur: 221.569 cm; Hauteur 2: 0 cm; Rayon Arc: 0 cm; Rayon Cercle: 0 cm; Demi-axe horizontal: 0 cm; Demi-axe vertical: 0 cm; IFC_Pset_Géométrie_GRILLE - décalage: 0 cm; Offset latéral: 0 cm; Décalage supérieur: 0 cm; Décalage inférieur: 0 cm; Nombre accrochages latéraux: 0; Nombre d'accrochages supérieurs: 0; Nombre accrochages inférieurs: 0; IFC_Pset_Géométrie_Niche - Présent: no; Stratigraphie: Paroi en béton armé [120,00]; Épaisseur: 12 cm; Alignement: Intérieur; Décalage: 0 cm; IFC_Pset_Système de Référence Altimétrique_INFÉRIEUR - NIVEAU: Rez-de-Jardin (Rez-de-Jardin 15545); delta: 7.40519e-12 cm; sous Niveau: <aucun>; IFC_Pset_Données Métré - Surface de l'Ouverture: 39700 cm2; Surface de l'Ébrasement: 0 cm2; Surface du Seuil: 0 cm2; Surface du Seuil intérieur: 0 cm2; Volume du seuil: 0 cm3; Volume du seuil intérieur: 0 cm3; Surface de la Niche: 0 cm2; Surface de la Grille: 0 cm2; Volume de la Grille: 0 cm3
Baie 568902 | Rez-de-Jardin | 568902 | 114 | 9006 | 1 | -746779066 | Description: _VTO_Baie; CTLG_EXTERNAL_LINK - 1, DocType: 9; 1, Tag: 211; 1, Crc: -732809594; IFC_Pset_Caractéristiques - ID: 568902; Numérotation: 133; Numéro niveau: 02; Titre niveau: Rez-de-Jardin; IFC_Pset_Géométrie_Allège - Hauteur: 0 cm; Stratigraphie: ...; Épaisseur: 0 cm; IFC_Pset_Géométrie_Ébrasement - Présent: no; Côté supérieur: no; Côté INFÉRIEUR: no; Épaisseur extérieure: 0 cm; Épaisseur latérale gauche: 0 cm; Épaisseur latérale droite: 0 cm; Épiasseur latérale supérieure: 0 cm; Épaisseur diagonale gauche: 0 cm; Épaisseur diagonale droite: 0 cm; Épaisseur diagonale inférieure: 0 cm; Épaisseur diagonale supérieure: 0 cm; Épaisseur intérieur: 0 cm; IFC_Pset_Géométrie_Seuil - Type: Aucun; Épaisseur: 0 cm; Épaisseur interne: 0 cm; Décalage séparation: 0 cm; Appui extérieur: 0 cm; Appui intérieur: 0 cm; Côté latéral externe: 0 cm; Côté latéral interne: 0 cm; IFC_Pset_Géométrie_Chambranle - Position: Aucun; Épaisseur Chambranle intérieur: 0 cm; Longueur Chambranle intérieur: 0 cm; Superposition Chambranle intérieur: 0 cm; Épaisseur Intrados: 0 cm; Épaisseur Chambranle extérieur: 0 cm; Largeur Chambranle extérieur: 0 cm; Superposition Chambranle extérieur: 0 cm; Épaisseur Intrados extérieur: 0 cm; Décalage séparation intrados: 0 cm; IFC_Pset_Géométrie_CORNICHE depuis profil - Position: Aucune; sets with these values: 2; IFC_Pset_Géométrie_CORNICHE Extérieure à partir d'un profil - Décalage: 0; Angle: 0 deg; Symétrie: no; Fermer: no; sets with these values: 2; IFC_Pset_Géométrie_BASE Extérieure à partir d'un profil - Angle: 0 deg; Symétrie: no; Côté: 0 cm; sets with these values: 2; IFC_Pset_Géométrie - Côté extérieur: 0; Invertir (dte/gche): no; Invertir (intérieur/extérieur): no; Forme: Rectangle; Largeur: 84.8614 cm; Hauteur: 200.597 cm; Hauteur 2: 0 cm; Rayon Arc: 0 cm; Rayon Cercle: 0 cm; Demi-axe horizontal: 0 cm; Demi-axe vertical: 0 cm; IFC_Pset_Géométrie_GRILLE - décalage: 0 cm; Offset latéral: 0 cm; Décalage supérieur: 0 cm; Décalage inférieur: 0 cm; Nombre accrochages latéraux: 0; Nombre d'accrochages supérieurs: 0; Nombre accrochages inférieurs: 0; IFC_Pset_Géométrie_Niche - Présent: no; Stratigraphie: Paroi en béton armé [120,00]; Épaisseur: 12 cm; Alignement: Intérieur; Décalage: 0 cm; IFC_Pset_Système de Référence Altimétrique_INFÉRIEUR - NIVEAU: Rez-de-Jardin (Rez-de-Jardin 15545); delta: 107 cm; sous Niveau: <aucun>; IFC_Pset_Données Métré - Surface de l'Ouverture: 17000 cm2; Surface de l'Ébrasement: 0 cm2; Surface du Seuil: 0 cm2; Surface du Seuil intérieur: 0 cm2; Volume du seuil: 0 cm3; Volume du seuil intérieur: 0 cm3; Surface de la Niche: 0 cm2; Surface de la Grille: 0 cm2; Volume de la Grille: 0 cm3
4294966384_11 | Rez-de-Jardin | -912 | 2002 | 2002 | 0 | -1292786862
4294966389_11 | Rez-de-Jardin | -907 | 2002 | 2002 | 0 | -1292786862
4294966465_12 | Rez-de-Jardin | -831 | 2002 | 2002 | 0 | -1292786862
4294966503_17 | Rez-de-Jardin | -793 | 2002 | 2002 | 0 | -1292786862
4294966499_11 | Rez-de-Jardin | -797 | 2002 | 2002 | 0 | -1292786862
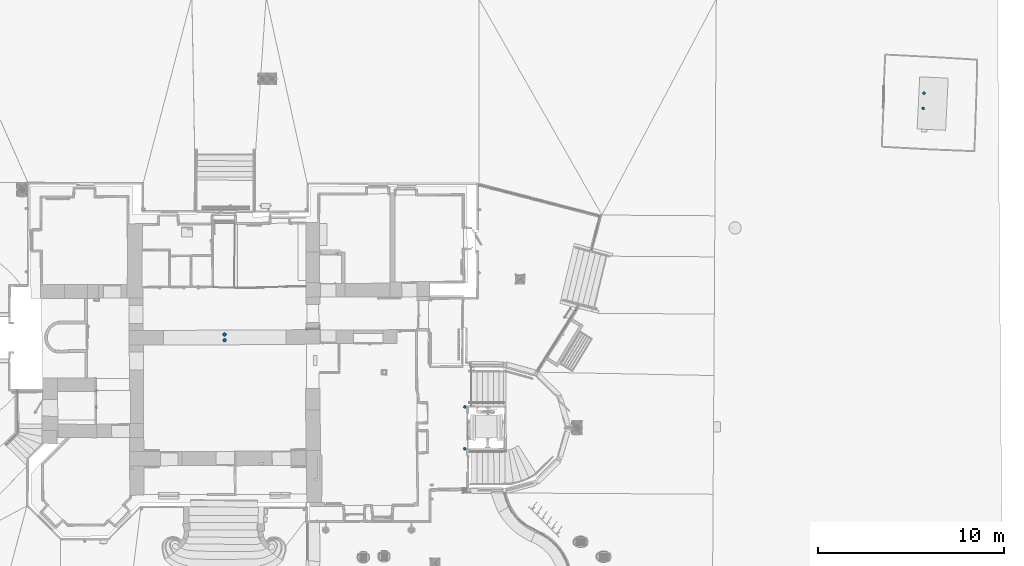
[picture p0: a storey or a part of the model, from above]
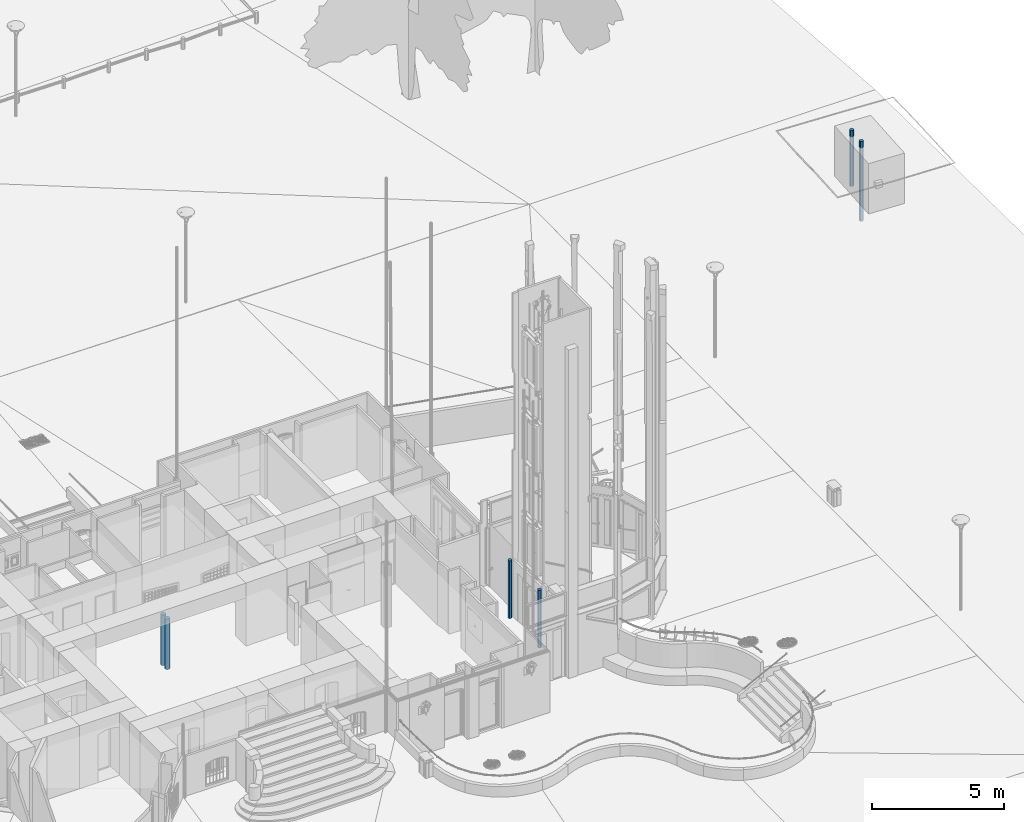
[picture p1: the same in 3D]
Properties of the parts of a building model (IFC2X3), part 10 of 37

# IfcOpeningElement: Opening (367)
Name | In | __RECOGNIZE__, ID | TPLG | TPLG_OD | GENERATE | 0, Crc
4294966470_12 | Rez-de-Jardin | -826 | 2002 | 2002 | 0 | -1292786862
4294966325_12 | Rez-de-Jardin | -971 | 2002 | 2002 | 0 | -1292786862
4294966358_11 | Rez-de-Jardin | -938 | 2002 | 2002 | 0 | -1292786862
4294966342_11 | Rez-de-Jardin | -954 | 2002 | 2002 | 0 | -1292786862
4294966467_12 | Rez-de-Jardin | -829 | 2002 | 2002 | 0 | -1292786862
4294966466_11 | Rez-de-Jardin | -830 | 2002 | 2002 | 0 | -1292786862
4294966464_12 | Rez-de-Jardin | -832 | 2002 | 2002 | 0 | -1292786862
4294966475_12 | Rez-de-Jardin | -821 | 2002 | 2002 | 0 | -1292786862
4294966473_11 | Rez-de-Jardin | -823 | 2002 | 2002 | 0 | -1292786862
4294966357_12 | Rez-de-Jardin | -939 | 2002 | 2002 | 0 | -1292786862
4294966479_12 | Rez-de-Jardin | -817 | 2002 | 2002 | 0 | -1292786862
4294966474_11 | Rez-de-Jardin | -822 | 2002 | 2002 | 0 | -1292786862
4294966364_11 | Rez-de-Jardin | -932 | 2002 | 2002 | 0 | -1292786862
4294966359_11 | Rez-de-Jardin | -937 | 2002 | 2002 | 0 | -1292786862
4294966319_11 | Rez-de-Jardin | -977 | 2002 | 2002 | 0 | -1292786862
4294966320_12 | Rez-de-Jardin | -976 | 2002 | 2002 | 0 | -1292786862
Baie 78719 | Rez-de-Jardin | 78719 | 114 | 9006 | 1 | -746779066 | Description: _VTO_Baie; CTLG_EXTERNAL_LINK - 1, DocType: 9; 1, Tag: 211; 1, Crc: -732809594; IFC_Pset_Caractéristiques - ID: 78719; Numérotation: 023; Numéro niveau: 02; Titre niveau: Rez-de-Jardin; IFC_Pset_Géométrie_Allège - Hauteur: 0 cm; Stratigraphie: ...; Épaisseur: 0 cm; IFC_Pset_Géométrie_Ébrasement - Présent: no; Côté supérieur: no; Côté INFÉRIEUR: no; Épaisseur extérieure: 0 cm; Épaisseur latérale gauche: 0 cm; Épaisseur latérale droite: 0 cm; Épiasseur latérale supérieure: 0 cm; Épaisseur diagonale gauche: 0 cm; Épaisseur diagonale droite: 0 cm; Épaisseur diagonale inférieure: 0 cm; Épaisseur diagonale supérieure: 0 cm; Épaisseur intérieur: 0 cm; IFC_Pset_Géométrie_Seuil - Type: Aucun; Épaisseur: 0 cm; Épaisseur interne: 0 cm; Décalage séparation: 0 cm; Appui extérieur: 0 cm; Appui intérieur: 0 cm; Côté latéral externe: 0 cm; Côté latéral interne: 0 cm; IFC_Pset_Géométrie_Chambranle - Position: Aucun; Épaisseur Chambranle intérieur: 0 cm; Longueur Chambranle intérieur: 0 cm; Superposition Chambranle intérieur: 0 cm; Épaisseur Intrados: 0 cm; Épaisseur Chambranle extérieur: 0 cm; Largeur Chambranle extérieur: 0 cm; Superposition Chambranle extérieur: 0 cm; Épaisseur Intrados extérieur: 0 cm; Décalage séparation intrados: 0 cm; IFC_Pset_Géométrie_CORNICHE depuis profil - Position: Aucune; sets with these values: 2; IFC_Pset_Géométrie_CORNICHE Extérieure à partir d'un profil - Décalage: 0; Angle: 0 deg; Symétrie: no; Fermer: no; sets with these values: 2; IFC_Pset_Géométrie_BASE Extérieure à partir d'un profil - Angle: 0 deg; Symétrie: no; Côté: 0 cm; sets with these values: 2; IFC_Pset_Géométrie - Côté extérieur: 1; Invertir (dte/gche): no; Invertir (intérieur/extérieur): no; Forme: Arc + Rectangle; Largeur: 175.96 cm; Hauteur: 220 cm; Hauteur 2: 0 cm; Rayon Arc: 19.4433 cm; Rayon Cercle: 0 cm; Demi-axe horizontal: 0 cm; Demi-axe vertical: 0 cm; IFC_Pset_Géométrie_GRILLE - décalage: 0 cm; Offset latéral: 0 cm; Décalage supérieur: 0 cm; Décalage inférieur: 0 cm; Nombre accrochages latéraux: 0; Nombre d'accrochages supérieurs: 0; Nombre accrochages inférieurs: 0; IFC_Pset_Géométrie_Niche - Présent: no; Stratigraphie: Paroi en béton armé [120,00]; Épaisseur: 12 cm; Alignement: Intérieur; Décalage: 0 cm; IFC_Pset_Système de Référence Altimétrique_INFÉRIEUR - NIVEAU: Rez-de-Jardin (Rez-de-Jardin 15545); delta: -1.96732e-11 cm; sous Niveau: <aucun>; IFC_Pset_Données Métré - Surface de l'Ouverture: 41000 cm2; Surface de l'Ébrasement: 0 cm2; Surface du Seuil: 0 cm2; Surface du Seuil intérieur: 0 cm2; Volume du seuil: 0 cm3; Volume du seuil intérieur: 0 cm3; Surface de la Niche: 0 cm2; Surface de la Grille: 0 cm2; Volume de la Grille: 0 cm3
4294966557_11 | Rez-de-Jardin | -739 | 2002 | 2002 | 0 | -1292786862
4294966356_11 | Rez-de-Jardin | -940 | 2002 | 2002 | 0 | -1292786862
4294966360_11 | Rez-de-Jardin | -936 | 2002 | 2002 | 0 | -1292786862
4294966355_12 | Rez-de-Jardin | -941 | 2002 | 2002 | 0 | -1292786862
4294966472_12 | Rez-de-Jardin | -824 | 2002 | 2002 | 0 | -1292786862
4294966338_12 | Rez-de-Jardin | -958 | 2002 | 2002 | 0 | -1292786862
4294966476_12 | Rez-de-Jardin | -820 | 2002 | 2002 | 0 | -1292786862
4294966337_11 | Rez-de-Jardin | -959 | 2002 | 2002 | 0 | -1292786862
Baie 78034 | Rez-de-Jardin | 78034 | 114 | 9006 | 1 | -746779066 | Description: _VTO_Baie; CTLG_EXTERNAL_LINK - 1, DocType: 9; 1, Tag: 211; 1, Crc: 2019374073; IFC_Pset_Caractéristiques - ID: 78034; Numérotation: 019; Numéro niveau: 02; Titre niveau: Rez-de-Jardin; IFC_Pset_Géométrie_Allège - Hauteur: 0 cm; Stratigraphie: ...; Épaisseur: 0 cm; IFC_Pset_Géométrie_Ébrasement - Présent: no; Côté supérieur: no; Côté INFÉRIEUR: no; Épaisseur extérieure: 0 cm; Épaisseur latérale gauche: 0 cm; Épaisseur latérale droite: 0 cm; Épiasseur latérale supérieure: 0 cm; Épaisseur diagonale gauche: 0 cm; Épaisseur diagonale droite: 0 cm; Épaisseur diagonale inférieure: 0 cm; Épaisseur diagonale supérieure: 0 cm; Épaisseur intérieur: 0 cm; IFC_Pset_Géométrie_Seuil - Type: Aucun; Épaisseur: 0 cm; Épaisseur interne: 0 cm; Décalage séparation: 0 cm; Appui extérieur: 0 cm; Appui intérieur: 0 cm; Côté latéral externe: 0 cm; Côté latéral interne: 0 cm; IFC_Pset_Géométrie_Chambranle - Position: Aucun; Épaisseur Chambranle intérieur: 0 cm; Longueur Chambranle intérieur: 0 cm; Superposition Chambranle intérieur: 0 cm; Épaisseur Intrados: 0 cm; Épaisseur Chambranle extérieur: 0 cm; Largeur Chambranle extérieur: 0 cm; Superposition Chambranle extérieur: 0 cm; Épaisseur Intrados extérieur: 0 cm; Décalage séparation intrados: 0 cm; IFC_Pset_Géométrie_CORNICHE depuis profil - Position: Aucune; sets with these values: 2; IFC_Pset_Géométrie_CORNICHE Extérieure à partir d'un profil - Décalage: 0; Angle: 0 deg; Symétrie: no; Fermer: no; sets with these values: 2; IFC_Pset_Géométrie_BASE Extérieure à partir d'un profil - Angle: 0 deg; Symétrie: no; Côté: 0 cm; sets with these values: 2; IFC_Pset_Géométrie - Côté extérieur: 1; Invertir (dte/gche): no; Invertir (intérieur/extérieur): no; Forme: Arc + Rectangle; Largeur: 96.8997 cm; Hauteur: 216 cm; Hauteur 2: 0 cm; Rayon Arc: 10.1641 cm; Rayon Cercle: 0 cm; Demi-axe horizontal: 0 cm; Demi-axe vertical: 0 cm; IFC_Pset_Géométrie_GRILLE - décalage: 0 cm; Offset latéral: 0 cm; Décalage supérieur: 0 cm; Décalage inférieur: 0 cm; Nombre accrochages latéraux: 0; Nombre d'accrochages supérieurs: 0; Nombre accrochages inférieurs: 0; IFC_Pset_Géométrie_Niche - Présent: no; Stratigraphie: default [130,00]; Épaisseur: 13 cm; Alignement: Intérieur; Décalage: 0 cm; IFC_Pset_Système de Référence Altimétrique_INFÉRIEUR - NIVEAU: Rez-de-Jardin (Rez-de-Jardin 15545); delta: -1.95399e-11 cm; sous Niveau: <aucun>; IFC_Pset_Données Métré - Surface de l'Ouverture: 21600 cm2; Surface de l'Ébrasement: 0 cm2; Surface du Seuil: 0 cm2; Surface du Seuil intérieur: 0 cm2; Volume du seuil: 0 cm3; Volume du seuil intérieur: 0 cm3; Surface de la Niche: 0 cm2; Surface de la Grille: 0 cm2; Volume de la Grille: 0 cm3
Baie 78745 | Rez-de-Jardin | 78745 | 114 | 9006 | 1 | -746779066 | Description: _VTO_Baie; CTLG_EXTERNAL_LINK - 1, DocType: 9; 1, Tag: 211; 1, Crc: -732809594; IFC_Pset_Caractéristiques - ID: 78745; Numérotation: 025; Numéro niveau: 02; Titre niveau: Rez-de-Jardin; IFC_Pset_Géométrie_Allège - Hauteur: 0 cm; Stratigraphie: ...; Épaisseur: 0 cm; IFC_Pset_Géométrie_Ébrasement - Présent: no; Côté supérieur: no; Côté INFÉRIEUR: no; Épaisseur extérieure: 0 cm; Épaisseur latérale gauche: 0 cm; Épaisseur latérale droite: 0 cm; Épiasseur latérale supérieure: 0 cm; Épaisseur diagonale gauche: 0 cm; Épaisseur diagonale droite: 0 cm; Épaisseur diagonale inférieure: 0 cm; Épaisseur diagonale supérieure: 0 cm; Épaisseur intérieur: 0 cm; IFC_Pset_Géométrie_Seuil - Type: Aucun; Épaisseur: 0 cm; Épaisseur interne: 0 cm; Décalage séparation: 0 cm; Appui extérieur: 0 cm; Appui intérieur: 0 cm; Côté latéral externe: 0 cm; Côté latéral interne: 0 cm; IFC_Pset_Géométrie_Chambranle - Position: Aucun; Épaisseur Chambranle intérieur: 0 cm; Longueur Chambranle intérieur: 0 cm; Superposition Chambranle intérieur: 0 cm; Épaisseur Intrados: 0 cm; Épaisseur Chambranle extérieur: 0 cm; Largeur Chambranle extérieur: 0 cm; Superposition Chambranle extérieur: 0 cm; Épaisseur Intrados extérieur: 0 cm; Décalage séparation intrados: 0 cm; IFC_Pset_Géométrie_CORNICHE depuis profil - Position: Aucune; sets with these values: 2; IFC_Pset_Géométrie_CORNICHE Extérieure à partir d'un profil - Décalage: 0; Angle: 0 deg; Symétrie: no; Fermer: no; sets with these values: 2; IFC_Pset_Géométrie_BASE Extérieure à partir d'un profil - Angle: 0 deg; Symétrie: no; Côté: 0 cm; sets with these values: 2; IFC_Pset_Géométrie - Côté extérieur: 1; Invertir (dte/gche): no; Invertir (intérieur/extérieur): no; Forme: Arc + Rectangle; Largeur: 96 cm; Hauteur: 215 cm; Hauteur 2: 0 cm; Rayon Arc: 12.7635 cm; Rayon Cercle: 0 cm; Demi-axe horizontal: 0 cm; Demi-axe vertical: 0 cm; IFC_Pset_Géométrie_GRILLE - décalage: 0 cm; Offset latéral: 0 cm; Décalage supérieur: 0 cm; Décalage inférieur: 0 cm; Nombre accrochages latéraux: 0; Nombre d'accrochages supérieurs: 0; Nombre accrochages inférieurs: 0; IFC_Pset_Géométrie_Niche - Présent: no; Stratigraphie: Paroi en béton armé [120,00]; Épaisseur: 12 cm; Alignement: Intérieur; Décalage: 0 cm; IFC_Pset_Système de Référence Altimétrique_INFÉRIEUR - NIVEAU: Rez-de-Jardin (Rez-de-Jardin 15545); delta: 0.546045 cm; sous Niveau: <aucun>; IFC_Pset_Données Métré - Surface de l'Ouverture: 21500 cm2; Surface de l'Ébrasement: 0 cm2; Surface du Seuil: 0 cm2; Surface du Seuil intérieur: 0 cm2; Volume du seuil: 0 cm3; Volume du seuil intérieur: 0 cm3; Surface de la Niche: 0 cm2; Surface de la Grille: 0 cm2; Volume de la Grille: 0 cm3
4294966478_12 | Rez-de-Jardin | -818 | 2002 | 2002 | 0 | -1292786862
4294966327_12 | Rez-de-Jardin | -969 | 2002 | 2002 | 0 | -1292786862
4294966322_11 | Rez-de-Jardin | -974 | 2002 | 2002 | 0 | -1292786862
4294966330_11 | Rez-de-Jardin | -966 | 2002 | 2002 | 0 | -1292786862
4294966339_12 | Rez-de-Jardin | -957 | 2002 | 2002 | 0 | -1292786862
4294966323_12 | Rez-de-Jardin | -973 | 2002 | 2002 | 0 | -1292786862
4294966477_11 | Rez-de-Jardin | -819 | 2002 | 2002 | 0 | -1292786862
Baie 230406 | Rez-de-Jardin | 230406 | 114 | 9006 | 1 | -746779066 | Description: _VTO_Baie; CTLG_EXTERNAL_LINK - 1, DocType: 9; 1, Tag: 211; 1, Crc: -1554559915; IFC_Pset_Caractéristiques - ID: 230406; Numérotation: 046; Numéro niveau: 02; Titre niveau: Rez-de-Jardin; IFC_Pset_Géométrie_Allège - Hauteur: 0 cm; Stratigraphie: ...; Épaisseur: 0 cm; IFC_Pset_Géométrie_Ébrasement - Présent: no; Côté supérieur: no; Côté INFÉRIEUR: no; Épaisseur extérieure: 0 cm; Épaisseur latérale gauche: 0 cm; Épaisseur latérale droite: 0 cm; Épiasseur latérale supérieure: 0 cm; Épaisseur diagonale gauche: 0 cm; Épaisseur diagonale droite: 0 cm; Épaisseur diagonale inférieure: 0 cm; Épaisseur diagonale supérieure: 0 cm; Épaisseur intérieur: 0 cm; IFC_Pset_Géométrie_Seuil - Type: Aucun; Épaisseur: 0 cm; Épaisseur interne: 0 cm; Décalage séparation: 0 cm; Appui extérieur: 0 cm; Appui intérieur: 0 cm; Côté latéral externe: 0 cm; Côté latéral interne: 0 cm; IFC_Pset_Géométrie_Chambranle - Position: Aucun; Épaisseur Chambranle intérieur: 0 cm; Longueur Chambranle intérieur: 0 cm; Superposition Chambranle intérieur: 0 cm; Épaisseur Intrados: 0 cm; Épaisseur Chambranle extérieur: 0 cm; Largeur Chambranle extérieur: 0 cm; Superposition Chambranle extérieur: 0 cm; Épaisseur Intrados extérieur: 0 cm; Décalage séparation intrados: 0 cm; IFC_Pset_Géométrie_CORNICHE depuis profil - Position: Aucune; sets with these values: 2; IFC_Pset_Géométrie_CORNICHE Extérieure à partir d'un profil - Décalage: 0; Angle: 0 deg; Symétrie: no; Fermer: no; sets with these values: 2; IFC_Pset_Géométrie_BASE Extérieure à partir d'un profil - Angle: 0 deg; Symétrie: no; Côté: 0 cm; sets with these values: 2; IFC_Pset_Géométrie - Côté extérieur: 0; Invertir (dte/gche): no; Invertir (intérieur/extérieur): no; Forme: Arc + Rectangle; Largeur: 100.272 cm; Hauteur: 220.925 cm; Hauteur 2: 0 cm; Rayon Arc: 12.7112 cm; Rayon Cercle: 0 cm; Demi-axe horizontal: 0 cm; Demi-axe vertical: 0 cm; IFC_Pset_Géométrie_GRILLE - décalage: 0 cm; Offset latéral: 0 cm; Décalage supérieur: 0 cm; Décalage inférieur: 0 cm; Nombre accrochages latéraux: 0; Nombre d'accrochages supérieurs: 0; Nombre accrochages inférieurs: 0; IFC_Pset_Géométrie_Niche - Présent: no; Stratigraphie: default [80,00]; Épaisseur: 8 cm; Alignement: Intérieur; Décalage: 0 cm; IFC_Pset_Système de Référence Altimétrique_INFÉRIEUR - NIVEAU: Rez-de-Jardin (Rez-de-Jardin 15545); delta: -1.94067e-11 cm; sous Niveau: <aucun>; IFC_Pset_Données Métré - Surface de l'Ouverture: 23000 cm2; Surface de l'Ébrasement: 0 cm2; Surface du Seuil: 0 cm2; Surface du Seuil intérieur: 0 cm2; Volume du seuil: 0 cm3; Volume du seuil intérieur: 0 cm3; Surface de la Niche: 0 cm2; Surface de la Grille: 0 cm2; Volume de la Grille: 0 cm3
4294966552_12 | Rez-de-Jardin | -744 | 2002 | 2002 | 0 | -1292786862
4294966554_12 | Rez-de-Jardin | -742 | 2002 | 2002 | 0 | -1292786862
4294966553_12 | Rez-de-Jardin | -743 | 2002 | 2002 | 0 | -1292786862
4294966555_12 | Rez-de-Jardin | -741 | 2002 | 2002 | 0 | -1292786862
Baie 356362 | Rez-de-Jardin | 356362 | 114 | 9006 | 1 | -746779066 | Description: _VTO_Baie; CTLG_EXTERNAL_LINK - 1, DocType: 9; 1, Tag: 211; 1, Crc: -1554559915; IFC_Pset_Caractéristiques - ID: 356362; Numérotation: 052; Numéro niveau: 02; Titre niveau: Rez-de-Jardin; IFC_Pset_Géométrie_Allège - Hauteur: 0 cm; Stratigraphie: ...; Épaisseur: 0 cm; IFC_Pset_Géométrie_Ébrasement - Présent: no; Côté supérieur: no; Côté INFÉRIEUR: no; Épaisseur extérieure: 0 cm; Épaisseur latérale gauche: 0 cm; Épaisseur latérale droite: 0 cm; Épiasseur latérale supérieure: 0 cm; Épaisseur diagonale gauche: 0 cm; Épaisseur diagonale droite: 0 cm; Épaisseur diagonale inférieure: 0 cm; Épaisseur diagonale supérieure: 0 cm; Épaisseur intérieur: 0 cm; IFC_Pset_Géométrie_Seuil - Type: Aucun; Épaisseur: 0 cm; Épaisseur interne: 0 cm; Décalage séparation: 0 cm; Appui extérieur: 0 cm; Appui intérieur: 0 cm; Côté latéral externe: 0 cm; Côté latéral interne: 0 cm; IFC_Pset_Géométrie_Chambranle - Position: Aucun; Épaisseur Chambranle intérieur: 0 cm; Longueur Chambranle intérieur: 0 cm; Superposition Chambranle intérieur: 0 cm; Épaisseur Intrados: 0 cm; Épaisseur Chambranle extérieur: 0 cm; Largeur Chambranle extérieur: 0 cm; Superposition Chambranle extérieur: 0 cm; Épaisseur Intrados extérieur: 0 cm; Décalage séparation intrados: 0 cm; IFC_Pset_Géométrie_CORNICHE depuis profil - Position: Aucune; sets with these values: 2; IFC_Pset_Géométrie_CORNICHE Extérieure à partir d'un profil - Décalage: 0; Angle: 0 deg; Symétrie: no; Fermer: no; sets with these values: 2; IFC_Pset_Géométrie_BASE Extérieure à partir d'un profil - Angle: 0 deg; Symétrie: no; Côté: 0 cm; sets with these values: 2; IFC_Pset_Géométrie - Côté extérieur: 0; Invertir (dte/gche): no; Invertir (intérieur/extérieur): no; Forme: Arc + Rectangle; Largeur: 112.532 cm; Hauteur: 222.994 cm; Hauteur 2: 0 cm; Rayon Arc: 12.9916 cm; Rayon Cercle: 0 cm; Demi-axe horizontal: 0 cm; Demi-axe vertical: 0 cm; IFC_Pset_Géométrie_GRILLE - décalage: 0 cm; Offset latéral: 0 cm; Décalage supérieur: 0 cm; Décalage inférieur: 0 cm; Nombre accrochages latéraux: 0; Nombre d'accrochages supérieurs: 0; Nombre accrochages inférieurs: 0; IFC_Pset_Géométrie_Niche - Présent: no; Stratigraphie: default [80,00]; Épaisseur: 8 cm; Alignement: Intérieur; Décalage: 0 cm; IFC_Pset_Système de Référence Altimétrique_INFÉRIEUR - NIVEAU: Rez-de-Jardin (Rez-de-Jardin 15545); delta: -1.93623e-11 cm; sous Niveau: <aucun>; IFC_Pset_Données Métré - Surface de l'Ouverture: 26100 cm2; Surface de l'Ébrasement: 0 cm2; Surface du Seuil: 0 cm2; Surface du Seuil intérieur: 0 cm2; Volume du seuil: 0 cm3; Volume du seuil intérieur: 0 cm3; Surface de la Niche: 0 cm2; Surface de la Grille: 0 cm2; Volume de la Grille: 0 cm3
4294966551_12 | Rez-de-Jardin | -745 | 2002 | 2002 | 0 | -1292786862
4294966548_12 | Rez-de-Jardin | -748 | 2002 | 2002 | 0 | -1292786862
4294966546_12 | Rez-de-Jardin | -750 | 2002 | 2002 | 0 | -1292786862
Baie 357470 | Rez-de-Jardin | 357470 | 114 | 9006 | 1 | -746779066 | Description: _VTO_Baie; CTLG_EXTERNAL_LINK - 1, DocType: 9; 1, Tag: 211; 1, Crc: -1554559915; IFC_Pset_Caractéristiques - ID: 357470; Numérotation: 053; Numéro niveau: 02; Titre niveau: Rez-de-Jardin; IFC_Pset_Géométrie_Allège - Hauteur: 0 cm; Stratigraphie: ...; Épaisseur: 0 cm; IFC_Pset_Géométrie_Ébrasement - Présent: no; Côté supérieur: no; Côté INFÉRIEUR: no; Épaisseur extérieure: 0 cm; Épaisseur latérale gauche: 0 cm; Épaisseur latérale droite: 0 cm; Épiasseur latérale supérieure: 0 cm; Épaisseur diagonale gauche: 0 cm; Épaisseur diagonale droite: 0 cm; Épaisseur diagonale inférieure: 0 cm; Épaisseur diagonale supérieure: 0 cm; Épaisseur intérieur: 0 cm; IFC_Pset_Géométrie_Seuil - Type: Aucun; Épaisseur: 0 cm; Épaisseur interne: 0 cm; Décalage séparation: 0 cm; Appui extérieur: 0 cm; Appui intérieur: 0 cm; Côté latéral externe: 0 cm; Côté latéral interne: 0 cm; IFC_Pset_Géométrie_Chambranle - Position: Aucun; Épaisseur Chambranle intérieur: 0 cm; Longueur Chambranle intérieur: 0 cm; Superposition Chambranle intérieur: 0 cm; Épaisseur Intrados: 0 cm; Épaisseur Chambranle extérieur: 0 cm; Largeur Chambranle extérieur: 0 cm; Superposition Chambranle extérieur: 0 cm; Épaisseur Intrados extérieur: 0 cm; Décalage séparation intrados: 0 cm; IFC_Pset_Géométrie_CORNICHE depuis profil - Position: Aucune; sets with these values: 2; IFC_Pset_Géométrie_CORNICHE Extérieure à partir d'un profil - Décalage: 0; Angle: 0 deg; Symétrie: no; Fermer: no; sets with these values: 2; IFC_Pset_Géométrie_BASE Extérieure à partir d'un profil - Angle: 0 deg; Symétrie: no; Côté: 0 cm; sets with these values: 2; IFC_Pset_Géométrie - Côté extérieur: 1; Invertir (dte/gche): no; Invertir (intérieur/extérieur): no; Forme: Rectangle; Largeur: 155.975 cm; Hauteur: 267.996 cm; Hauteur 2: 0 cm; Rayon Arc: 0 cm; Rayon Cercle: 0 cm; Demi-axe horizontal: 0 cm; Demi-axe vertical: 0 cm; IFC_Pset_Géométrie_GRILLE - décalage: 0 cm; Offset latéral: 0 cm; Décalage supérieur: 0 cm; Décalage inférieur: 0 cm; Nombre accrochages latéraux: 0; Nombre d'accrochages supérieurs: 0; Nombre accrochages inférieurs: 0; IFC_Pset_Géométrie_Niche - Présent: no; Stratigraphie: default [80,00]; Épaisseur: 8 cm; Alignement: Intérieur; Décalage: 0 cm; IFC_Pset_Système de Référence Altimétrique_INFÉRIEUR - NIVEAU: Rez-de-Jardin (Rez-de-Jardin 15545); delta: 0.0000103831 cm; sous Niveau: <aucun>; IFC_Pset_Données Métré - Surface de l'Ouverture: 41800 cm2; Surface de l'Ébrasement: 0 cm2; Surface du Seuil: 0 cm2; Surface du Seuil intérieur: 0 cm2; Volume du seuil: 0 cm3; Volume du seuil intérieur: 0 cm3; Surface de la Niche: 0 cm2; Surface de la Grille: 0 cm2; Volume de la Grille: 0 cm3
Baie 357471 | Rez-de-Jardin | 357471 | 114 | 9006 | 1 | -746779066 | Description: _VTO_Baie; CTLG_EXTERNAL_LINK - 1, DocType: 9; 1, Tag: 211; 1, Crc: -1554559915; IFC_Pset_Caractéristiques - ID: 357471; Numérotation: 054; Numéro niveau: 02; Titre niveau: Rez-de-Jardin; IFC_Pset_Géométrie_Allège - Hauteur: 0 cm; Stratigraphie: ...; Épaisseur: 0 cm; IFC_Pset_Géométrie_Ébrasement - Présent: no; Côté supérieur: no; Côté INFÉRIEUR: no; Épaisseur extérieure: 0 cm; Épaisseur latérale gauche: 0 cm; Épaisseur latérale droite: 0 cm; Épiasseur latérale supérieure: 0 cm; Épaisseur diagonale gauche: 0 cm; Épaisseur diagonale droite: 0 cm; Épaisseur diagonale inférieure: 0 cm; Épaisseur diagonale supérieure: 0 cm; Épaisseur intérieur: 0 cm; IFC_Pset_Géométrie_Seuil - Type: Aucun; Épaisseur: 0 cm; Épaisseur interne: 0 cm; Décalage séparation: 0 cm; Appui extérieur: 0 cm; Appui intérieur: 0 cm; Côté latéral externe: 0 cm; Côté latéral interne: 0 cm; IFC_Pset_Géométrie_Chambranle - Position: Aucun; Épaisseur Chambranle intérieur: 0 cm; Longueur Chambranle intérieur: 0 cm; Superposition Chambranle intérieur: 0 cm; Épaisseur Intrados: 0 cm; Épaisseur Chambranle extérieur: 0 cm; Largeur Chambranle extérieur: 0 cm; Superposition Chambranle extérieur: 0 cm; Épaisseur Intrados extérieur: 0 cm; Décalage séparation intrados: 0 cm; IFC_Pset_Géométrie_CORNICHE depuis profil - Position: Aucune; sets with these values: 2; IFC_Pset_Géométrie_CORNICHE Extérieure à partir d'un profil - Décalage: 0; Angle: 0 deg; Symétrie: no; Fermer: no; sets with these values: 2; IFC_Pset_Géométrie_BASE Extérieure à partir d'un profil - Angle: 0 deg; Symétrie: no; Côté: 0 cm; sets with these values: 2; IFC_Pset_Géométrie - Côté extérieur: 1; Invertir (dte/gche): no; Invertir (intérieur/extérieur): no; Forme: Rectangle; Largeur: 146.773 cm; Hauteur: 257.679 cm; Hauteur 2: 0 cm; Rayon Arc: 0 cm; Rayon Cercle: 0 cm; Demi-axe horizontal: 0 cm; Demi-axe vertical: 0 cm; IFC_Pset_Géométrie_GRILLE - décalage: 0 cm; Offset latéral: 0 cm; Décalage supérieur: 0 cm; Décalage inférieur: 0 cm; Nombre accrochages latéraux: 0; Nombre d'accrochages supérieurs: 0; Nombre accrochages inférieurs: 0; IFC_Pset_Géométrie_Niche - Présent: no; Stratigraphie: default [80,00]; Épaisseur: 8 cm; Alignement: Intérieur; Décalage: 0 cm; IFC_Pset_Système de Référence Altimétrique_INFÉRIEUR - NIVEAU: Rez-de-Jardin (Rez-de-Jardin 15545); delta: 9.81829 cm; sous Niveau: <aucun>; IFC_Pset_Données Métré - Surface de l'Ouverture: 37800 cm2; Surface de l'Ébrasement: 0 cm2; Surface du Seuil: 0 cm2; Surface du Seuil intérieur: 0 cm2; Volume du seuil: 0 cm3; Volume du seuil intérieur: 0 cm3; Surface de la Niche: 0 cm2; Surface de la Grille: 0 cm2; Volume de la Grille: 0 cm3
Baie 361731 | Rez-de-Jardin | 361731 | 114 | 9006 | 1 | -746779066 | Description: _VTO_Baie; CTLG_EXTERNAL_LINK - 1, DocType: 9; 1, Tag: 211; 1, Crc: -732809594; IFC_Pset_Caractéristiques - ID: 361731; Numérotation: 056; Numéro niveau: 02; Titre niveau: Rez-de-Jardin; IFC_Pset_Géométrie_Allège - Hauteur: 0 cm; Stratigraphie: ...; Épaisseur: 0 cm; IFC_Pset_Géométrie_Ébrasement - Présent: no; Côté supérieur: no; Côté INFÉRIEUR: no; Épaisseur extérieure: 0 cm; Épaisseur latérale gauche: 0 cm; Épaisseur latérale droite: 0 cm; Épiasseur latérale supérieure: 0 cm; Épaisseur diagonale gauche: 0 cm; Épaisseur diagonale droite: 0 cm; Épaisseur diagonale inférieure: 0 cm; Épaisseur diagonale supérieure: 0 cm; Épaisseur intérieur: 0 cm; IFC_Pset_Géométrie_Seuil - Type: Aucun; Épaisseur: 0 cm; Épaisseur interne: 0 cm; Décalage séparation: 0 cm; Appui extérieur: 0 cm; Appui intérieur: 0 cm; Côté latéral externe: 0 cm; Côté latéral interne: 0 cm; IFC_Pset_Géométrie_Chambranle - Position: Aucun; Épaisseur Chambranle intérieur: 0 cm; Longueur Chambranle intérieur: 0 cm; Superposition Chambranle intérieur: 0 cm; Épaisseur Intrados: 0 cm; Épaisseur Chambranle extérieur: 0 cm; Largeur Chambranle extérieur: 0 cm; Superposition Chambranle extérieur: 0 cm; Épaisseur Intrados extérieur: 0 cm; Décalage séparation intrados: 0 cm; IFC_Pset_Géométrie_CORNICHE depuis profil - Position: Aucune; sets with these values: 2; IFC_Pset_Géométrie_CORNICHE Extérieure à partir d'un profil - Décalage: 0; Angle: 0 deg; Symétrie: no; Fermer: no; sets with these values: 2; IFC_Pset_Géométrie_BASE Extérieure à partir d'un profil - Angle: 0 deg; Symétrie: no; Côté: 0 cm; sets with these values: 2; IFC_Pset_Géométrie - Côté extérieur: 0; Invertir (dte/gche): no; Invertir (intérieur/extérieur): no; Forme: Arc + Rectangle; Largeur: 99.2886 cm; Hauteur: 221.404 cm; Hauteur 2: 0 cm; Rayon Arc: 11.6993 cm; Rayon Cercle: 0 cm; Demi-axe horizontal: 0 cm; Demi-axe vertical: 0 cm; IFC_Pset_Géométrie_GRILLE - décalage: 0 cm; Offset latéral: 0 cm; Décalage supérieur: 0 cm; Décalage inférieur: 0 cm; Nombre accrochages latéraux: 0; Nombre d'accrochages supérieurs: 0; Nombre accrochages inférieurs: 0; IFC_Pset_Géométrie_Niche - Présent: no; Stratigraphie: Paroi en béton armé [120,00]; Épaisseur: 12 cm; Alignement: Intérieur; Décalage: 0 cm; IFC_Pset_Système de Référence Altimétrique_INFÉRIEUR - NIVEAU: Rez-de-Jardin (Rez-de-Jardin 15545); delta: 8.88178e-14 cm; sous Niveau: <aucun>; IFC_Pset_Données Métré - Surface de l'Ouverture: 22800 cm2; Surface de l'Ébrasement: 0 cm2; Surface du Seuil: 0 cm2; Surface du Seuil intérieur: 0 cm2; Volume du seuil: 0 cm3; Volume du seuil intérieur: 0 cm3; Surface de la Niche: 0 cm2; Surface de la Grille: 0 cm2; Volume de la Grille: 0 cm3
4294966518_11 | Rez-de-Jardin | -778 | 2002 | 2002 | 0 | -1292786862
4294966385_11 | Rez-de-Jardin | -911 | 2002 | 2002 | 0 | -1292786862
4294966549_12 | Rez-de-Jardin | -747 | 2002 | 2002 | 0 | -1292786862
4294966547_11 | Rez-de-Jardin | -749 | 2002 | 2002 | 0 | -1292786862
4294966550_12 | Rez-de-Jardin | -746 | 2002 | 2002 | 0 | -1292786862
4294966520_11 | Rez-de-Jardin | -776 | 2002 | 2002 | 0 | -1292786862
4294966519_11 | Rez-de-Jardin | -777 | 2002 | 2002 | 0 | -1292786862
Baie 363236 | Rez-de-Jardin | 363236 | 114 | 9006 | 1 | -746779066 | Description: _VTO_Baie; CTLG_EXTERNAL_LINK - 1, DocType: 9; 1, Tag: 211; 1, Crc: -1554559915; IFC_Pset_Caractéristiques - ID: 363236; Numérotation: 061; Numéro niveau: 02; Titre niveau: Rez-de-Jardin; IFC_Pset_Géométrie_Allège - Hauteur: 0 cm; Stratigraphie: ...; Épaisseur: 0 cm; IFC_Pset_Géométrie_Ébrasement - Présent: no; Côté supérieur: no; Côté INFÉRIEUR: no; Épaisseur extérieure: 0 cm; Épaisseur latérale gauche: 0 cm; Épaisseur latérale droite: 0 cm; Épiasseur latérale supérieure: 0 cm; Épaisseur diagonale gauche: 0 cm; Épaisseur diagonale droite: 0 cm; Épaisseur diagonale inférieure: 0 cm; Épaisseur diagonale supérieure: 0 cm; Épaisseur intérieur: 0 cm; IFC_Pset_Géométrie_Seuil - Type: Aucun; Épaisseur: 0 cm; Épaisseur interne: 0 cm; Décalage séparation: 0 cm; Appui extérieur: 0 cm; Appui intérieur: 0 cm; Côté latéral externe: 0 cm; Côté latéral interne: 0 cm; IFC_Pset_Géométrie_Chambranle - Position: Aucun; Épaisseur Chambranle intérieur: 0 cm; Longueur Chambranle intérieur: 0 cm; Superposition Chambranle intérieur: 0 cm; Épaisseur Intrados: 0 cm; Épaisseur Chambranle extérieur: 0 cm; Largeur Chambranle extérieur: 0 cm; Superposition Chambranle extérieur: 0 cm; Épaisseur Intrados extérieur: 0 cm; Décalage séparation intrados: 0 cm; IFC_Pset_Géométrie_CORNICHE depuis profil - Position: Aucune; sets with these values: 2; IFC_Pset_Géométrie_CORNICHE Extérieure à partir d'un profil - Décalage: 0; Angle: 0 deg; Symétrie: no; Fermer: no; sets with these values: 2; IFC_Pset_Géométrie_BASE Extérieure à partir d'un profil - Angle: 0 deg; Symétrie: no; Côté: 0 cm; sets with these values: 2; IFC_Pset_Géométrie - Côté extérieur: 1; Invertir (dte/gche): no; Invertir (intérieur/extérieur): no; Forme: Arc + Rectangle; Largeur: 115.532 cm; Hauteur: 208.89 cm; Hauteur 2: 0 cm; Rayon Arc: 15.7878 cm; Rayon Cercle: 0 cm; Demi-axe horizontal: 0 cm; Demi-axe vertical: 0 cm; IFC_Pset_Géométrie_GRILLE - décalage: 0 cm; Offset latéral: 0 cm; Décalage supérieur: 0 cm; Décalage inférieur: 0 cm; Nombre accrochages latéraux: 0; Nombre d'accrochages supérieurs: 0; Nombre accrochages inférieurs: 0; IFC_Pset_Géométrie_Niche - Présent: no; Stratigraphie: default [80,00]; Épaisseur: 8 cm; Alignement: Intérieur; Décalage: 0 cm; IFC_Pset_Système de Référence Altimétrique_INFÉRIEUR - NIVEAU: Rez-de-Jardin (Rez-de-Jardin 15545); delta: 5.03228 cm; sous Niveau: <aucun>; IFC_Pset_Données Métré - Surface de l'Ouverture: 25400 cm2; Surface de l'Ébrasement: 0 cm2; Surface du Seuil: 0 cm2; Surface du Seuil intérieur: 0 cm2; Volume du seuil: 0 cm3; Volume du seuil intérieur: 0 cm3; Surface de la Niche: 0 cm2; Surface de la Grille: 0 cm2; Volume de la Grille: 0 cm3
4294966526_11 | Rez-de-Jardin | -770 | 2002 | 2002 | 0 | -1292786862
4294966321_11 | Rez-de-Jardin | -975 | 2002 | 2002 | 0 | -1292786862
4294966329_11 | Rez-de-Jardin | -967 | 2002 | 2002 | 0 | -1292786862
4294966328_11 | Rez-de-Jardin | -968 | 2002 | 2002 | 0 | -1292786862
4294966324_11 | Rez-de-Jardin | -972 | 2002 | 2002 | 0 | -1292786862
Baie 78627 | Rez-de-Jardin | 78627 | 114 | 9006 | 1 | -746779066 | Description: _VTO_Baie; CTLG_EXTERNAL_LINK - 1, DocType: 9; 1, Tag: 211; 1, Crc: -732809594; IFC_Pset_Caractéristiques - ID: 78627; Numérotation: 022; Numéro niveau: 02; Titre niveau: Rez-de-Jardin; IFC_Pset_Géométrie_Allège - Hauteur: 0 cm; Stratigraphie: ...; Épaisseur: 0 cm; IFC_Pset_Géométrie_Ébrasement - Présent: no; Côté supérieur: no; Côté INFÉRIEUR: no; Épaisseur extérieure: 0 cm; Épaisseur latérale gauche: 0 cm; Épaisseur latérale droite: 0 cm; Épiasseur latérale supérieure: 0 cm; Épaisseur diagonale gauche: 0 cm; Épaisseur diagonale droite: 0 cm; Épaisseur diagonale inférieure: 0 cm; Épaisseur diagonale supérieure: 0 cm; Épaisseur intérieur: 0 cm; IFC_Pset_Géométrie_Seuil - Type: Aucun; Épaisseur: 0 cm; Épaisseur interne: 0 cm; Décalage séparation: 0 cm; Appui extérieur: 0 cm; Appui intérieur: 0 cm; Côté latéral externe: 0 cm; Côté latéral interne: 0 cm; IFC_Pset_Géométrie_Chambranle - Position: Aucun; Épaisseur Chambranle intérieur: 0 cm; Longueur Chambranle intérieur: 0 cm; Superposition Chambranle intérieur: 0 cm; Épaisseur Intrados: 0 cm; Épaisseur Chambranle extérieur: 0 cm; Largeur Chambranle extérieur: 0 cm; Superposition Chambranle extérieur: 0 cm; Épaisseur Intrados extérieur: 0 cm; Décalage séparation intrados: 0 cm; IFC_Pset_Géométrie_CORNICHE depuis profil - Position: Aucune; sets with these values: 2; IFC_Pset_Géométrie_CORNICHE Extérieure à partir d'un profil - Décalage: 0; Angle: 0 deg; Symétrie: no; Fermer: no; sets with these values: 2; IFC_Pset_Géométrie_BASE Extérieure à partir d'un profil - Angle: 0 deg; Symétrie: no; Côté: 0 cm; sets with these values: 2; IFC_Pset_Géométrie - Côté extérieur: 1; Invertir (dte/gche): no; Invertir (intérieur/extérieur): no; Forme: Arc + Rectangle; Largeur: 96 cm; Hauteur: 220 cm; Hauteur 2: 0 cm; Rayon Arc: 9.32462 cm; Rayon Cercle: 0 cm; Demi-axe horizontal: 0 cm; Demi-axe vertical: 0 cm; IFC_Pset_Géométrie_GRILLE - décalage: 0 cm; Offset latéral: 0 cm; Décalage supérieur: 0 cm; Décalage inférieur: 0 cm; Nombre accrochages latéraux: 0; Nombre d'accrochages supérieurs: 0; Nombre accrochages inférieurs: 0; IFC_Pset_Géométrie_Niche - Présent: no; Stratigraphie: Paroi en béton armé [120,00]; Épaisseur: 12 cm; Alignement: Intérieur; Décalage: 0 cm; IFC_Pset_Système de Référence Altimétrique_INFÉRIEUR - NIVEAU: Rez-de-Jardin (Rez-de-Jardin 15545); delta: 1.50322 cm; sous Niveau: <aucun>; IFC_Pset_Données Métré - Surface de l'Ouverture: 21700 cm2; Surface de l'Ébrasement: 0 cm2; Surface du Seuil: 0 cm2; Surface du Seuil intérieur: 0 cm2; Volume du seuil: 0 cm3; Volume du seuil intérieur: 0 cm3; Surface de la Niche: 0 cm2; Surface de la Grille: 0 cm2; Volume de la Grille: 0 cm3
4294966326_11 | Rez-de-Jardin | -970 | 2002 | 2002 | 0 | -1292786862
4294966383_11 | Rez-de-Jardin | -913 | 2002 | 2002 | 0 | -1292786862
Baie 780725 | Rez-de-chaussée | 780725 | 114 | 9006 | 1 | -746779066 | Description: _VTO_Baie; CTLG_EXTERNAL_LINK - 1, DocType: 9; 1, Tag: 211; 1, Crc: 1582870039; IFC_Pset_Caractéristiques - ID: 780725; Numérotation: 158; Numéro niveau: 03; Titre niveau: Rez-de-chaussée; IFC_Pset_Géométrie_Allège - Hauteur: 0 cm; Stratigraphie: ...; Épaisseur: 0 cm; IFC_Pset_Géométrie_Ébrasement - Présent: no; Côté supérieur: no; Côté INFÉRIEUR: no; Épaisseur extérieure: 0 cm; Épaisseur latérale gauche: 0 cm; Épaisseur latérale droite: 0 cm; Épiasseur latérale supérieure: 0 cm; Épaisseur diagonale gauche: 0 cm; Épaisseur diagonale droite: 0 cm; Épaisseur diagonale inférieure: 0 cm; Épaisseur diagonale supérieure: 0 cm; Épaisseur intérieur: 0 cm; IFC_Pset_Géométrie_Seuil - Type: Aucun; Épaisseur: 0 cm; Épaisseur interne: 0 cm; Décalage séparation: 0 cm; Appui extérieur: 0 cm; Appui intérieur: 0 cm; Côté latéral externe: 0 cm; Côté latéral interne: 0 cm; IFC_Pset_Géométrie_Chambranle - Position: Aucun; Épaisseur Chambranle intérieur: 0 cm; Longueur Chambranle intérieur: 0 cm; Superposition Chambranle intérieur: 0 cm; Épaisseur Intrados: 0 cm; Épaisseur Chambranle extérieur: 0 cm; Largeur Chambranle extérieur: 0 cm; Superposition Chambranle extérieur: 0 cm; Épaisseur Intrados extérieur: 0 cm; Décalage séparation intrados: 0 cm; IFC_Pset_Géométrie_CORNICHE depuis profil - Position: Aucune; sets with these values: 2; IFC_Pset_Géométrie_CORNICHE Extérieure à partir d'un profil - Décalage: 0; Angle: 0 deg; Symétrie: no; Fermer: no; sets with these values: 2; IFC_Pset_Géométrie_BASE Extérieure à partir d'un profil - Angle: 0 deg; Symétrie: no; Côté: 0 cm; sets with these values: 2; IFC_Pset_Géométrie - Côté extérieur: 1; Invertir (dte/gche): no; Invertir (intérieur/extérieur): no; Forme: Rectangle; Largeur: 122.869 cm; Hauteur: 49 cm; Hauteur 2: 0 cm; Rayon Arc: 0 cm; Rayon Cercle: 0 cm; Demi-axe horizontal: 0 cm; Demi-axe vertical: 0 cm; IFC_Pset_Géométrie_GRILLE - décalage: 0 cm; Offset latéral: 0 cm; Décalage supérieur: 0 cm; Décalage inférieur: 0 cm; Nombre accrochages latéraux: 0; Nombre d'accrochages supérieurs: 0; Nombre accrochages inférieurs: 0; IFC_Pset_Géométrie_Niche - Présent: no; Stratigraphie: default [210,00]; Épaisseur: 21 cm; Alignement: Intérieur; Décalage: 0 cm; IFC_Pset_Système de Référence Altimétrique_INFÉRIEUR - NIVEAU: Rez-de-chaussée (Rez-de-chaussée 1047); delta: 0 cm; sous Niveau: <aucun>; IFC_Pset_Données Métré - Surface de l'Ouverture: 6000 cm2; Surface de l'Ébrasement: 0 cm2; Surface du Seuil: 0 cm2; Surface du Seuil intérieur: 0 cm2; Volume du seuil: 0 cm3; Volume du seuil intérieur: 0 cm3; Surface de la Niche: 0 cm2; Surface de la Grille: 0 cm2; Volume de la Grille: 0 cm3
4294966529_11 | Rez-de-chaussée | -767 | 2002 | 2002 | 0 | -1292786862
4294966515_11 | Rez-de-chaussée | -781 | 2002 | 2002 | 0 | -1292786862
4294966544_11 | Rez-de-chaussée | -752 | 2002 | 2002 | 0 | -1292786862
4294966541_11 | Rez-de-chaussée | -755 | 2002 | 2002 | 0 | -1292786862
4294966538_11 | Rez-de-chaussée | -758 | 2002 | 2002 | 0 | -1292786862
4294966540_11 | Rez-de-chaussée | -756 | 2002 | 2002 | 0 | -1292786862
4294966539_11 | Rez-de-chaussée | -757 | 2002 | 2002 | 0 | -1292786862
4294966545_11 | Rez-de-chaussée | -751 | 2002 | 2002 | 0 | -1292786862
4294966542_11 | Rez-de-chaussée | -754 | 2002 | 2002 | 0 | -1292786862
Baie 383891 | Rez-de-chaussée | 383891 | 114 | 9006 | 1 | -746779066 | Description: _VTO_Baie; CTLG_EXTERNAL_LINK - 1, DocType: 9; 1, Tag: 211; 1, Crc: -732809594; IFC_Pset_Caractéristiques - ID: 383891; Numérotation: 084; Numéro niveau: 03; Titre niveau: Rez-de-chaussée; IFC_Pset_Géométrie_Allège - Hauteur: 0 cm; Stratigraphie: ...; Épaisseur: 0 cm; IFC_Pset_Géométrie_Ébrasement - Présent: yes; Côté supérieur: no; Côté INFÉRIEUR: no; Épaisseur extérieure: 11 cm; Épaisseur latérale gauche: 3 cm; Épaisseur latérale droite: 3 cm; Épiasseur latérale supérieure: 3 cm; Épaisseur diagonale gauche: 0 cm; Épaisseur diagonale droite: 0 cm; Épaisseur diagonale inférieure: 0 cm; Épaisseur diagonale supérieure: 0 cm; Épaisseur intérieur: 0 cm; Données: [a : 110,00; b: 30,00; c: 0,00; d: 0,00] mm; IFC_Pset_Géométrie_Seuil - Type: Aucun; Épaisseur: 0 cm; Épaisseur interne: 0 cm; Décalage séparation: 0 cm; Appui extérieur: 0 cm; Appui intérieur: 0 cm; Côté latéral externe: 0 cm; Côté latéral interne: 0 cm; IFC_Pset_Géométrie_Chambranle - Position: Aucun; Épaisseur Chambranle intérieur: 0 cm; Longueur Chambranle intérieur: 0 cm; Superposition Chambranle intérieur: 0 cm; Épaisseur Intrados: 0 cm; Épaisseur Chambranle extérieur: 0 cm; Largeur Chambranle extérieur: 0 cm; Superposition Chambranle extérieur: 0 cm; Épaisseur Intrados extérieur: 0 cm; Décalage séparation intrados: 0 cm; IFC_Pset_Géométrie_CORNICHE depuis profil - Position: Aucune; sets with these values: 2; IFC_Pset_Géométrie_CORNICHE Extérieure à partir d'un profil - Décalage: 0; Angle: 0 deg; Symétrie: no; Fermer: no; sets with these values: 2; IFC_Pset_Géométrie_BASE Extérieure à partir d'un profil - Angle: 0 deg; Symétrie: no; Côté: 0 cm; sets with these values: 2; IFC_Pset_Géométrie - Côté extérieur: 1; Invertir (dte/gche): no; Invertir (intérieur/extérieur): yes; Forme: Rectangle; Largeur: 150.555 cm; Hauteur: 177.891 cm; Hauteur 2: 0 cm; Rayon Arc: 0 cm; Rayon Cercle: 0 cm; Demi-axe horizontal: 0 cm; Demi-axe vertical: 0 cm; IFC_Pset_Géométrie_GRILLE - décalage: 0 cm; Offset latéral: 0 cm; Décalage supérieur: 0 cm; Décalage inférieur: 0 cm; Nombre accrochages latéraux: 0; Nombre d'accrochages supérieurs: 0; Nombre accrochages inférieurs: 0; IFC_Pset_Géométrie_Niche - Présent: no; Stratigraphie: Paroi en béton armé [120,00]; Épaisseur: 12 cm; Alignement: Intérieur; Décalage: 0 cm; IFC_Pset_Système de Référence Altimétrique_INFÉRIEUR - NIVEAU: Rez-de-chaussée (Rez-de-chaussée 1047); delta: 0.0128504 cm; sous Niveau: <aucun>; IFC_Pset_Données Métré - Surface de l'Ouverture: 26800 cm2; Surface de l'Ébrasement: 6400 cm2; Surface du Seuil: 0 cm2; Surface du Seuil intérieur: 0 cm2; Volume du seuil: 0 cm3; Volume du seuil intérieur: 0 cm3; Surface de la Niche: 0 cm2; Surface de la Grille: 0 cm2; Volume de la Grille: 0 cm3
Baie 379599 | Rez-de-chaussée | 379599 | 114 | 9006 | 1 | -746779066 | Description: _VTO_Baie; CTLG_EXTERNAL_LINK - 1, DocType: 9; 1, Tag: 211; 1, Crc: -1554559915; IFC_Pset_Caractéristiques - ID: 379599; Numérotation: 075; Numéro niveau: 03; Titre niveau: Rez-de-chaussée; IFC_Pset_Géométrie_Allège - Hauteur: 0 cm; Stratigraphie: ...; Épaisseur: 0 cm; IFC_Pset_Géométrie_Ébrasement - Présent: yes; Côté supérieur: no; Côté INFÉRIEUR: no; Épaisseur extérieure: 11 cm; Épaisseur latérale gauche: 3 cm; Épaisseur latérale droite: 3 cm; Épiasseur latérale supérieure: 3 cm; Épaisseur diagonale gauche: 0 cm; Épaisseur diagonale droite: 0 cm; Épaisseur diagonale inférieure: 0 cm; Épaisseur diagonale supérieure: 0 cm; Épaisseur intérieur: 0 cm; Données: [a : 110,00; b: 30,00; c: 0,00; d: 0,00] mm; IFC_Pset_Géométrie_Seuil - Type: Aucun; Épaisseur: 0 cm; Épaisseur interne: 0 cm; Décalage séparation: 0 cm; Appui extérieur: 0 cm; Appui intérieur: 0 cm; Côté latéral externe: 0 cm; Côté latéral interne: 0 cm; IFC_Pset_Géométrie_Chambranle - Position: Aucun; Épaisseur Chambranle intérieur: 0 cm; Longueur Chambranle intérieur: 0 cm; Superposition Chambranle intérieur: 0 cm; Épaisseur Intrados: 0 cm; Épaisseur Chambranle extérieur: 0 cm; Largeur Chambranle extérieur: 0 cm; Superposition Chambranle extérieur: 0 cm; Épaisseur Intrados extérieur: 0 cm; Décalage séparation intrados: 0 cm; IFC_Pset_Géométrie_CORNICHE depuis profil - Position: Aucune; sets with these values: 2; IFC_Pset_Géométrie_CORNICHE Extérieure à partir d'un profil - Décalage: 0; Angle: 0 deg; Symétrie: no; Fermer: no; sets with these values: 2; IFC_Pset_Géométrie_BASE Extérieure à partir d'un profil - Angle: 0 deg; Symétrie: no; Côté: 0 cm; sets with these values: 2; IFC_Pset_Géométrie - Côté extérieur: 1; Invertir (dte/gche): no; Invertir (intérieur/extérieur): yes; Forme: Rectangle; Largeur: 29.8788 cm; Hauteur: 252.494 cm; Hauteur 2: 0 cm; Rayon Arc: 0 cm; Rayon Cercle: 0 cm; Demi-axe horizontal: 0 cm; Demi-axe vertical: 0 cm; IFC_Pset_Géométrie_GRILLE - décalage: 0 cm; Offset latéral: 0 cm; Décalage supérieur: 0 cm; Décalage inférieur: 0 cm; Nombre accrochages latéraux: 0; Nombre d'accrochages supérieurs: 0; Nombre accrochages inférieurs: 0; IFC_Pset_Géométrie_Niche - Présent: no; Stratigraphie: default [80,00]; Épaisseur: 8 cm; Alignement: Intérieur; Décalage: 0 cm; IFC_Pset_Système de Référence Altimétrique_INFÉRIEUR - NIVEAU: Rez-de-chaussée (Rez-de-chaussée 1047); delta: 49.8413 cm; sous Niveau: <aucun>; IFC_Pset_Données Métré - Surface de l'Ouverture: 7500 cm2; Surface de l'Ébrasement: 9100 cm2; Surface du Seuil: 0 cm2; Surface du Seuil intérieur: 0 cm2; Volume du seuil: 0 cm3; Volume du seuil intérieur: 0 cm3; Surface de la Niche: 0 cm2; Surface de la Grille: 0 cm2; Volume de la Grille: 0 cm3
Baie 379600 | Rez-de-chaussée | 379600 | 114 | 9006 | 1 | -746779066 | Description: _VTO_Baie; CTLG_EXTERNAL_LINK - 1, DocType: 9; 1, Tag: 211; 1, Crc: -1554559915; IFC_Pset_Caractéristiques - ID: 379600; Numérotation: 076; Numéro niveau: 03; Titre niveau: Rez-de-chaussée; IFC_Pset_Géométrie_Allège - Hauteur: 0 cm; Stratigraphie: ...; Épaisseur: 0 cm; IFC_Pset_Géométrie_Ébrasement - Présent: yes; Côté supérieur: no; Côté INFÉRIEUR: no; Épaisseur extérieure: 11 cm; Épaisseur latérale gauche: 3 cm; Épaisseur latérale droite: 3 cm; Épiasseur latérale supérieure: 3 cm; Épaisseur diagonale gauche: 0 cm; Épaisseur diagonale droite: 0 cm; Épaisseur diagonale inférieure: 0 cm; Épaisseur diagonale supérieure: 0 cm; Épaisseur intérieur: 0 cm; Données: [a : 110,00; b: 30,00; c: 0,00; d: 0,00] mm; IFC_Pset_Géométrie_Seuil - Type: Aucun; Épaisseur: 0 cm; Épaisseur interne: 0 cm; Décalage séparation: 0 cm; Appui extérieur: 0 cm; Appui intérieur: 0 cm; Côté latéral externe: 0 cm; Côté latéral interne: 0 cm; IFC_Pset_Géométrie_Chambranle - Position: Aucun; Épaisseur Chambranle intérieur: 0 cm; Longueur Chambranle intérieur: 0 cm; Superposition Chambranle intérieur: 0 cm; Épaisseur Intrados: 0 cm; Épaisseur Chambranle extérieur: 0 cm; Largeur Chambranle extérieur: 0 cm; Superposition Chambranle extérieur: 0 cm; Épaisseur Intrados extérieur: 0 cm; Décalage séparation intrados: 0 cm; IFC_Pset_Géométrie_CORNICHE depuis profil - Position: Aucune; sets with these values: 2; IFC_Pset_Géométrie_CORNICHE Extérieure à partir d'un profil - Décalage: 0; Angle: 0 deg; Symétrie: no; Fermer: no; sets with these values: 2; IFC_Pset_Géométrie_BASE Extérieure à partir d'un profil - Angle: 0 deg; Symétrie: no; Côté: 0 cm; sets with these values: 2; IFC_Pset_Géométrie - Côté extérieur: 1; Invertir (dte/gche): no; Invertir (intérieur/extérieur): yes; Forme: Rectangle; Largeur: 30.1072 cm; Hauteur: 252.494 cm; Hauteur 2: 0 cm; Rayon Arc: 0 cm; Rayon Cercle: 0 cm; Demi-axe horizontal: 0 cm; Demi-axe vertical: 0 cm; IFC_Pset_Géométrie_GRILLE - décalage: 0 cm; Offset latéral: 0 cm; Décalage supérieur: 0 cm; Décalage inférieur: 0 cm; Nombre accrochages latéraux: 0; Nombre d'accrochages supérieurs: 0; Nombre accrochages inférieurs: 0; IFC_Pset_Géométrie_Niche - Présent: no; Stratigraphie: default [80,00]; Épaisseur: 8 cm; Alignement: Intérieur; Décalage: 0 cm; IFC_Pset_Système de Référence Altimétrique_INFÉRIEUR - NIVEAU: Rez-de-chaussée (Rez-de-chaussée 1047); delta: 49.8 cm; sous Niveau: <aucun>; IFC_Pset_Données Métré - Surface de l'Ouverture: 7600 cm2; Surface de l'Ébrasement: 9100 cm2; Surface du Seuil: 0 cm2; Surface du Seuil intérieur: 0 cm2; Volume du seuil: 0 cm3; Volume du seuil intérieur: 0 cm3; Surface de la Niche: 0 cm2; Surface de la Grille: 0 cm2; Volume de la Grille: 0 cm3
Baie 379481 | Rez-de-chaussée | 379481 | 114 | 9006 | 1 | -746779066 | Description: _VTO_Baie; CTLG_EXTERNAL_LINK - 1, DocType: 9; 1, Tag: 211; 1, Crc: -1554559915; IFC_Pset_Caractéristiques - ID: 379481; Numérotation: 071; Numéro niveau: 03; Titre niveau: Rez-de-chaussée; IFC_Pset_Géométrie_Allège - Hauteur: 0 cm; Stratigraphie: ...; Épaisseur: 0 cm; IFC_Pset_Géométrie_Ébrasement - Présent: no; Côté supérieur: no; Côté INFÉRIEUR: no; Épaisseur extérieure: 0 cm; Épaisseur latérale gauche: 0 cm; Épaisseur latérale droite: 0 cm; Épiasseur latérale supérieure: 0 cm; Épaisseur diagonale gauche: 0 cm; Épaisseur diagonale droite: 0 cm; Épaisseur diagonale inférieure: 0 cm; Épaisseur diagonale supérieure: 0 cm; Épaisseur intérieur: 0 cm; IFC_Pset_Géométrie_Seuil - Type: Aucun; Épaisseur: 0 cm; Épaisseur interne: 0 cm; Décalage séparation: 0 cm; Appui extérieur: 0 cm; Appui intérieur: 0 cm; Côté latéral externe: 0 cm; Côté latéral interne: 0 cm; IFC_Pset_Géométrie_Chambranle - Position: Aucun; Épaisseur Chambranle intérieur: 0 cm; Longueur Chambranle intérieur: 0 cm; Superposition Chambranle intérieur: 0 cm; Épaisseur Intrados: 0 cm; Épaisseur Chambranle extérieur: 0 cm; Largeur Chambranle extérieur: 0 cm; Superposition Chambranle extérieur: 0 cm; Épaisseur Intrados extérieur: 0 cm; Décalage séparation intrados: 0 cm; IFC_Pset_Géométrie_CORNICHE depuis profil - Position: Aucune; sets with these values: 2; IFC_Pset_Géométrie_CORNICHE Extérieure à partir d'un profil - Décalage: 0; Angle: 0 deg; Symétrie: no; Fermer: no; sets with these values: 2; IFC_Pset_Géométrie_BASE Extérieure à partir d'un profil - Angle: 0 deg; Symétrie: no; Côté: 0 cm; sets with these values: 2; IFC_Pset_Géométrie - Côté extérieur: 0; Invertir (dte/gche): no; Invertir (intérieur/extérieur): no; Forme: Arc + Rectangle; Largeur: 201.818 cm; Hauteur: 317.921 cm; Hauteur 2: 0 cm; Rayon Arc: 25.0027 cm; Rayon Cercle: 0 cm; Demi-axe horizontal: 0 cm; Demi-axe vertical: 0 cm; IFC_Pset_Géométrie_GRILLE - décalage: 0 cm; Offset latéral: 0 cm; Décalage supérieur: 0 cm; Décalage inférieur: 0 cm; Nombre accrochages latéraux: 0; Nombre d'accrochages supérieurs: 0; Nombre accrochages inférieurs: 0; IFC_Pset_Géométrie_Niche - Présent: no; Stratigraphie: default [80,00]; Épaisseur: 8 cm; Alignement: Intérieur; Décalage: 0 cm; IFC_Pset_Système de Référence Altimétrique_INFÉRIEUR - NIVEAU: Rez-de-chaussée (Rez-de-chaussée 1047); delta: 48.6 cm; sous Niveau: <aucun>; IFC_Pset_Données Métré - Surface de l'Ouverture: 67500 cm2; Surface de l'Ébrasement: 0 cm2; Surface du Seuil: 0 cm2; Surface du Seuil intérieur: 0 cm2; Volume du seuil: 0 cm3; Volume du seuil intérieur: 0 cm3; Surface de la Niche: 0 cm2; Surface de la Grille: 0 cm2; Volume de la Grille: 0 cm3
Baie 379595 | Rez-de-chaussée | 379595 | 114 | 9006 | 1 | -746779066 | Description: _VTO_Baie; CTLG_EXTERNAL_LINK - 1, DocType: 9; 1, Tag: 211; 1, Crc: -1554559915; IFC_Pset_Caractéristiques - ID: 379595; Numérotation: 072; Numéro niveau: 03; Titre niveau: Rez-de-chaussée; IFC_Pset_Géométrie_Allège - Hauteur: 0 cm; Stratigraphie: ...; Épaisseur: 0 cm; IFC_Pset_Géométrie_Ébrasement - Présent: yes; Côté supérieur: no; Côté INFÉRIEUR: no; Épaisseur extérieure: 11 cm; Épaisseur latérale gauche: 3 cm; Épaisseur latérale droite: 3 cm; Épiasseur latérale supérieure: 3 cm; Épaisseur diagonale gauche: 0 cm; Épaisseur diagonale droite: 0 cm; Épaisseur diagonale inférieure: 0 cm; Épaisseur diagonale supérieure: 0 cm; Épaisseur intérieur: 0 cm; Données: [a : 110,00; b: 30,00; c: 0,00; d: 0,00] mm; IFC_Pset_Géométrie_Seuil - Type: Aucun; Épaisseur: 0 cm; Épaisseur interne: 0 cm; Décalage séparation: 0 cm; Appui extérieur: 0 cm; Appui intérieur: 0 cm; Côté latéral externe: 0 cm; Côté latéral interne: 0 cm; IFC_Pset_Géométrie_Chambranle - Position: Aucun; Épaisseur Chambranle intérieur: 0 cm; Longueur Chambranle intérieur: 0 cm; Superposition Chambranle intérieur: 0 cm; Épaisseur Intrados: 0 cm; Épaisseur Chambranle extérieur: 0 cm; Largeur Chambranle extérieur: 0 cm; Superposition Chambranle extérieur: 0 cm; Épaisseur Intrados extérieur: 0 cm; Décalage séparation intrados: 0 cm; IFC_Pset_Géométrie_CORNICHE depuis profil - Position: Aucune; sets with these values: 2; IFC_Pset_Géométrie_CORNICHE Extérieure à partir d'un profil - Décalage: 0; Angle: 0 deg; Symétrie: no; Fermer: no; sets with these values: 2; IFC_Pset_Géométrie_BASE Extérieure à partir d'un profil - Angle: 0 deg; Symétrie: no; Côté: 0 cm; sets with these values: 2; IFC_Pset_Géométrie - Côté extérieur: 0; Invertir (dte/gche): no; Invertir (intérieur/extérieur): no; Forme: Rectangle; Largeur: 130.302 cm; Hauteur: 345.312 cm; Hauteur 2: 0 cm; Rayon Arc: 0 cm; Rayon Cercle: 0 cm; Demi-axe horizontal: 0 cm; Demi-axe vertical: 0 cm; IFC_Pset_Géométrie_GRILLE - décalage: 0 cm; Offset latéral: 0 cm; Décalage supérieur: 0 cm; Décalage inférieur: 0 cm; Nombre accrochages latéraux: 0; Nombre d'accrochages supérieurs: 0; Nombre accrochages inférieurs: 0; IFC_Pset_Géométrie_Niche - Présent: no; Stratigraphie: default [80,00]; Épaisseur: 8 cm; Alignement: Intérieur; Décalage: 0 cm; IFC_Pset_Système de Référence Altimétrique_INFÉRIEUR - NIVEAU: Rez-de-chaussée (Rez-de-chaussée 1047); delta: 48.5125 cm; sous Niveau: <aucun>; IFC_Pset_Données Métré - Surface de l'Ouverture: 45000 cm2; Surface de l'Ébrasement: 12400 cm2; Surface du Seuil: 0 cm2; Surface du Seuil intérieur: 0 cm2; Volume du seuil: 0 cm3; Volume du seuil intérieur: 0 cm3; Surface de la Niche: 0 cm2; Surface de la Grille: 0 cm2; Volume de la Grille: 0 cm3
Baie 379596 | Rez-de-chaussée | 379596 | 114 | 9006 | 1 | -746779066 | Description: _VTO_Baie; CTLG_EXTERNAL_LINK - 1, DocType: 9; 1, Tag: 211; 1, Crc: -1554559915; IFC_Pset_Caractéristiques - ID: 379596; Numérotation: 073; Numéro niveau: 03; Titre niveau: Rez-de-chaussée; IFC_Pset_Géométrie_Allège - Hauteur: 0 cm; Stratigraphie: ...; Épaisseur: 0 cm; IFC_Pset_Géométrie_Ébrasement - Présent: yes; Côté supérieur: no; Côté INFÉRIEUR: no; Épaisseur extérieure: 11 cm; Épaisseur latérale gauche: 3 cm; Épaisseur latérale droite: 3 cm; Épiasseur latérale supérieure: 3 cm; Épaisseur diagonale gauche: 0 cm; Épaisseur diagonale droite: 0 cm; Épaisseur diagonale inférieure: 0 cm; Épaisseur diagonale supérieure: 0 cm; Épaisseur intérieur: 0 cm; Données: [a : 110,00; b: 30,00; c: 0,00; d: 0,00] mm; IFC_Pset_Géométrie_Seuil - Type: Aucun; Épaisseur: 0 cm; Épaisseur interne: 0 cm; Décalage séparation: 0 cm; Appui extérieur: 0 cm; Appui intérieur: 0 cm; Côté latéral externe: 0 cm; Côté latéral interne: 0 cm; IFC_Pset_Géométrie_Chambranle - Position: Aucun; Épaisseur Chambranle intérieur: 0 cm; Longueur Chambranle intérieur: 0 cm; Superposition Chambranle intérieur: 0 cm; Épaisseur Intrados: 0 cm; Épaisseur Chambranle extérieur: 0 cm; Largeur Chambranle extérieur: 0 cm; Superposition Chambranle extérieur: 0 cm; Épaisseur Intrados extérieur: 0 cm; Décalage séparation intrados: 0 cm; IFC_Pset_Géométrie_CORNICHE depuis profil - Position: Aucune; sets with these values: 2; IFC_Pset_Géométrie_CORNICHE Extérieure à partir d'un profil - Décalage: 0; Angle: 0 deg; Symétrie: no; Fermer: no; sets with these values: 2; IFC_Pset_Géométrie_BASE Extérieure à partir d'un profil - Angle: 0 deg; Symétrie: no; Côté: 0 cm; sets with these values: 2; IFC_Pset_Géométrie - Côté extérieur: 0; Invertir (dte/gche): no; Invertir (intérieur/extérieur): no; Forme: Rectangle; Largeur: 130.023 cm; Hauteur: 343.201 cm; Hauteur 2: 0 cm; Rayon Arc: 0 cm; Rayon Cercle: 0 cm; Demi-axe horizontal: 0 cm; Demi-axe vertical: 0 cm; IFC_Pset_Géométrie_GRILLE - décalage: 0 cm; Offset latéral: 0 cm; Décalage supérieur: 0 cm; Décalage inférieur: 0 cm; Nombre accrochages latéraux: 0; Nombre d'accrochages supérieurs: 0; Nombre accrochages inférieurs: 0; IFC_Pset_Géométrie_Niche - Présent: no; Stratigraphie: default [80,00]; Épaisseur: 8 cm; Alignement: Intérieur; Décalage: 0 cm; IFC_Pset_Système de Référence Altimétrique_INFÉRIEUR - NIVEAU: Rez-de-chaussée (Rez-de-chaussée 1047); delta: 50.5 cm; sous Niveau: <aucun>; IFC_Pset_Données Métré - Surface de l'Ouverture: 44600 cm2; Surface de l'Ébrasement: 12400 cm2; Surface du Seuil: 0 cm2; Surface du Seuil intérieur: 0 cm2; Volume du seuil: 0 cm3; Volume du seuil intérieur: 0 cm3; Surface de la Niche: 0 cm2; Surface de la Grille: 0 cm2; Volume de la Grille: 0 cm3
Baie 379597 | Rez-de-chaussée | 379597 | 114 | 9006 | 1 | -746779066 | Description: _VTO_Baie; CTLG_EXTERNAL_LINK - 1, DocType: 9; 1, Tag: 211; 1, Crc: -1554559915; IFC_Pset_Caractéristiques - ID: 379597; Numérotation: 074; Numéro niveau: 03; Titre niveau: Rez-de-chaussée; IFC_Pset_Géométrie_Allège - Hauteur: 0 cm; Stratigraphie: ...; Épaisseur: 0 cm; IFC_Pset_Géométrie_Ébrasement - Présent: yes; Côté supérieur: no; Côté INFÉRIEUR: no; Épaisseur extérieure: 11 cm; Épaisseur latérale gauche: 3 cm; Épaisseur latérale droite: 3 cm; Épiasseur latérale supérieure: 3 cm; Épaisseur diagonale gauche: 0 cm; Épaisseur diagonale droite: 0 cm; Épaisseur diagonale inférieure: 0 cm; Épaisseur diagonale supérieure: 0 cm; Épaisseur intérieur: 0 cm; Données: [a : 110,00; b: 30,00; c: 0,00; d: 0,00] mm; IFC_Pset_Géométrie_Seuil - Type: Aucun; Épaisseur: 0 cm; Épaisseur interne: 0 cm; Décalage séparation: 0 cm; Appui extérieur: 0 cm; Appui intérieur: 0 cm; Côté latéral externe: 0 cm; Côté latéral interne: 0 cm; IFC_Pset_Géométrie_Chambranle - Position: Aucun; Épaisseur Chambranle intérieur: 0 cm; Longueur Chambranle intérieur: 0 cm; Superposition Chambranle intérieur: 0 cm; Épaisseur Intrados: 0 cm; Épaisseur Chambranle extérieur: 0 cm; Largeur Chambranle extérieur: 0 cm; Superposition Chambranle extérieur: 0 cm; Épaisseur Intrados extérieur: 0 cm; Décalage séparation intrados: 0 cm; IFC_Pset_Géométrie_CORNICHE depuis profil - Position: Aucune; sets with these values: 2; IFC_Pset_Géométrie_CORNICHE Extérieure à partir d'un profil - Décalage: 0; Angle: 0 deg; Symétrie: no; Fermer: no; sets with these values: 2; IFC_Pset_Géométrie_BASE Extérieure à partir d'un profil - Angle: 0 deg; Symétrie: no; Côté: 0 cm; sets with these values: 2; IFC_Pset_Géométrie - Côté extérieur: 1; Invertir (dte/gche): no; Invertir (intérieur/extérieur): yes; Forme: Rectangle; Largeur: 130.46 cm; Hauteur: 345.873 cm; Hauteur 2: 0 cm; Rayon Arc: 0 cm; Rayon Cercle: 0 cm; Demi-axe horizontal: 0 cm; Demi-axe vertical: 0 cm; IFC_Pset_Géométrie_GRILLE - décalage: 0 cm; Offset latéral: 0 cm; Décalage supérieur: 0 cm; Décalage inférieur: 0 cm; Nombre accrochages latéraux: 0; Nombre d'accrochages supérieurs: 0; Nombre accrochages inférieurs: 0; IFC_Pset_Géométrie_Niche - Présent: no; Stratigraphie: default [80,00]; Épaisseur: 8 cm; Alignement: Intérieur; Décalage: 0 cm; IFC_Pset_Système de Référence Altimétrique_INFÉRIEUR - NIVEAU: Rez-de-chaussée (Rez-de-chaussée 1047); delta: 47.1915 cm; sous Niveau: <aucun>; IFC_Pset_Données Métré - Surface de l'Ouverture: 45100 cm2; Surface de l'Ébrasement: 12500 cm2; Surface du Seuil: 0 cm2; Surface du Seuil intérieur: 0 cm2; Volume du seuil: 0 cm3; Volume du seuil intérieur: 0 cm3; Surface de la Niche: 0 cm2; Surface de la Grille: 0 cm2; Volume de la Grille: 0 cm3
Baie 380010 | Rez-de-chaussée | 380010 | 114 | 9006 | 1 | -746779066 | Description: _VTO_Baie; CTLG_EXTERNAL_LINK - 1, DocType: 9; 1, Tag: 211; 1, Crc: -732809594; IFC_Pset_Caractéristiques - ID: 380010; Numérotation: 082; Numéro niveau: 03; Titre niveau: Rez-de-chaussée; IFC_Pset_Géométrie_Allège - Hauteur: 0 cm; Stratigraphie: ...; Épaisseur: 0 cm; IFC_Pset_Géométrie_Ébrasement - Présent: yes; Côté supérieur: no; Côté INFÉRIEUR: no; Épaisseur extérieure: 11 cm; Épaisseur latérale gauche: 3 cm; Épaisseur latérale droite: 3 cm; Épiasseur latérale supérieure: 3 cm; Épaisseur diagonale gauche: 0 cm; Épaisseur diagonale droite: 0 cm; Épaisseur diagonale inférieure: 0 cm; Épaisseur diagonale supérieure: 0 cm; Épaisseur intérieur: 0 cm; Données: [a : 110,00; b [gche]: 30,00; b [dte]: 30,00; b [sup]: 30,00; c [gche]: 0,00; c [dte]: 0,00; c [inf]: 0,00; c [sup]: 0,00; d: 0,00] mm; IFC_Pset_Géométrie_Seuil - Type: Aucun; Épaisseur: 0 cm; Épaisseur interne: 0 cm; Décalage séparation: 0 cm; Appui extérieur: 0 cm; Appui intérieur: 0 cm; Côté latéral externe: 0 cm; Côté latéral interne: 0 cm; IFC_Pset_Géométrie_Chambranle - Position: Aucun; Épaisseur Chambranle intérieur: 0 cm; Longueur Chambranle intérieur: 0 cm; Superposition Chambranle intérieur: 0 cm; Épaisseur Intrados: 0 cm; Épaisseur Chambranle extérieur: 0 cm; Largeur Chambranle extérieur: 0 cm; Superposition Chambranle extérieur: 0 cm; Épaisseur Intrados extérieur: 0 cm; Décalage séparation intrados: 0 cm; IFC_Pset_Géométrie_CORNICHE depuis profil - Position: Aucune; sets with these values: 2; IFC_Pset_Géométrie_CORNICHE Extérieure à partir d'un profil - Décalage: 0; Angle: 0 deg; Symétrie: no; Fermer: no; sets with these values: 2; IFC_Pset_Géométrie_BASE Extérieure à partir d'un profil - Angle: 0 deg; Symétrie: no; Côté: 0 cm; sets with these values: 2; IFC_Pset_Géométrie - Côté extérieur: 0; Invertir (dte/gche): no; Invertir (intérieur/extérieur): no; Forme: Arc + Rectangle; Largeur: 130.196 cm; Hauteur: 292.841 cm; Hauteur 2: 0 cm; Rayon Arc: 14.4069 cm; Rayon Cercle: 0 cm; Demi-axe horizontal: 0 cm; Demi-axe vertical: 0 cm; IFC_Pset_Géométrie_GRILLE - décalage: 0 cm; Offset latéral: 0 cm; Décalage supérieur: 0 cm; Décalage inférieur: 0 cm; Nombre accrochages latéraux: 0; Nombre d'accrochages supérieurs: 0; Nombre accrochages inférieurs: 0; IFC_Pset_Géométrie_Niche - Présent: no; Stratigraphie: Paroi en béton armé [120,00]; Épaisseur: 12 cm; Alignement: Intérieur; Décalage: 0 cm; IFC_Pset_Système de Référence Altimétrique_INFÉRIEUR - NIVEAU: Rez-de-chaussée (Rez-de-chaussée 1047); delta: 38.9298 cm; sous Niveau: <aucun>; IFC_Pset_Données Métré - Surface de l'Ouverture: 39700 cm2; Surface de l'Ébrasement: 13100 cm2; Surface du Seuil: 0 cm2; Surface du Seuil intérieur: 0 cm2; Volume du seuil: 0 cm3; Volume du seuil intérieur: 0 cm3; Surface de la Niche: 0 cm2; Surface de la Grille: 0 cm2; Volume de la Grille: 0 cm3
Baie 380009 | Rez-de-chaussée | 380009 | 114 | 9006 | 1 | -746779066 | Description: _VTO_Baie; CTLG_EXTERNAL_LINK - 1, DocType: 9; 1, Tag: 211; 1, Crc: -732809594; IFC_Pset_Caractéristiques - ID: 380009; Numérotation: 081; Numéro niveau: 03; Titre niveau: Rez-de-chaussée; IFC_Pset_Géométrie_Allège - Hauteur: 0 cm; Stratigraphie: ...; Épaisseur: 0 cm; IFC_Pset_Géométrie_Ébrasement - Présent: no; Côté supérieur: no; Côté INFÉRIEUR: no; Épaisseur extérieure: 0 cm; Épaisseur latérale gauche: 0 cm; Épaisseur latérale droite: 0 cm; Épiasseur latérale supérieure: 0 cm; Épaisseur diagonale gauche: 0 cm; Épaisseur diagonale droite: 0 cm; Épaisseur diagonale inférieure: 0 cm; Épaisseur diagonale supérieure: 0 cm; Épaisseur intérieur: 0 cm; IFC_Pset_Géométrie_Seuil - Type: Aucun; Épaisseur: 0 cm; Épaisseur interne: 0 cm; Décalage séparation: 0 cm; Appui extérieur: 0 cm; Appui intérieur: 0 cm; Côté latéral externe: 0 cm; Côté latéral interne: 0 cm; IFC_Pset_Géométrie_Chambranle - Position: Aucun; Épaisseur Chambranle intérieur: 0 cm; Longueur Chambranle intérieur: 0 cm; Superposition Chambranle intérieur: 0 cm; Épaisseur Intrados: 0 cm; Épaisseur Chambranle extérieur: 0 cm; Largeur Chambranle extérieur: 0 cm; Superposition Chambranle extérieur: 0 cm; Épaisseur Intrados extérieur: 0 cm; Décalage séparation intrados: 0 cm; IFC_Pset_Géométrie_CORNICHE depuis profil - Position: Aucune; sets with these values: 2; IFC_Pset_Géométrie_CORNICHE Extérieure à partir d'un profil - Décalage: 0; Angle: 0 deg; Symétrie: no; Fermer: no; sets with these values: 2; IFC_Pset_Géométrie_BASE Extérieure à partir d'un profil - Angle: 0 deg; Symétrie: no; Côté: 0 cm; sets with these values: 2; IFC_Pset_Géométrie - Côté extérieur: 1; Invertir (dte/gche): no; Invertir (intérieur/extérieur): no; Forme: Arc + Rectangle; Largeur: 330.994 cm; Hauteur: 333.309 cm; Hauteur 2: 0 cm; Rayon Arc: 36.7802 cm; Rayon Cercle: 0 cm; Demi-axe horizontal: 0 cm; Demi-axe vertical: 0 cm; IFC_Pset_Géométrie_GRILLE - décalage: 0 cm; Offset latéral: 0 cm; Décalage supérieur: 0 cm; Décalage inférieur: 0 cm; Nombre accrochages latéraux: 0; Nombre d'accrochages supérieurs: 0; Nombre accrochages inférieurs: 0; IFC_Pset_Géométrie_Niche - Présent: no; Stratigraphie: Paroi en béton armé [120,00]; Épaisseur: 12 cm; Alignement: Intérieur; Décalage: 0 cm; IFC_Pset_Système de Référence Altimétrique_INFÉRIEUR - NIVEAU: Rez-de-chaussée (Rez-de-chaussée 1047); delta: 2.09782 cm; sous Niveau: <aucun>; IFC_Pset_Données Métré - Surface de l'Ouverture: 118400 cm2; Surface de l'Ébrasement: 0 cm2; Surface du Seuil: 0 cm2; Surface du Seuil intérieur: 0 cm2; Volume du seuil: 0 cm3; Volume du seuil intérieur: 0 cm3; Surface de la Niche: 0 cm2; Surface de la Grille: 0 cm2; Volume de la Grille: 0 cm3
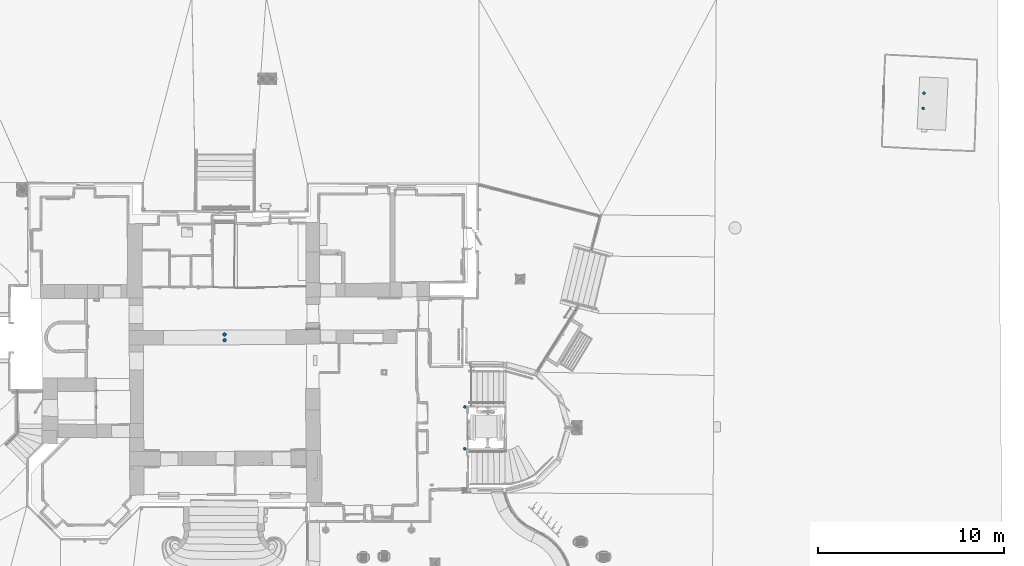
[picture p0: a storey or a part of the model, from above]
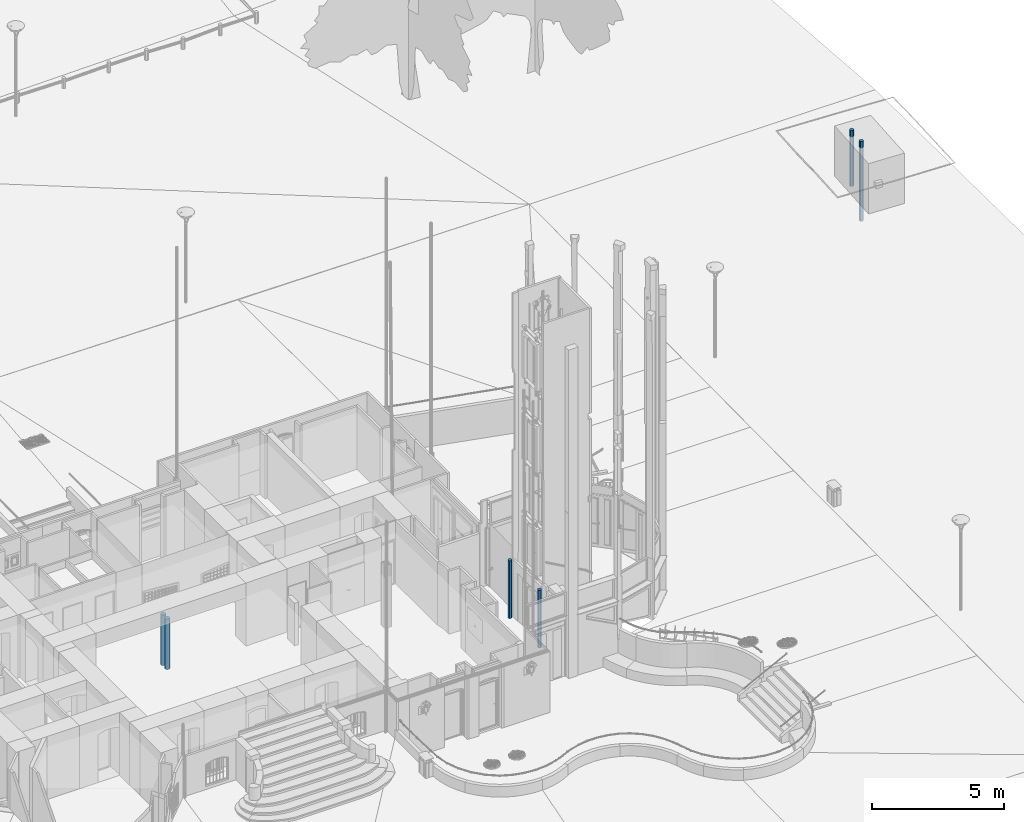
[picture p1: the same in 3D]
Properties of the parts of a building model (IFC2X3), part 11 of 37

# IfcOpeningElement: Opening (367)
Name | In | __RECOGNIZE__, ID | TPLG | TPLG_OD | GENERATE | 0, Crc
Baie 380008 | Rez-de-chaussée | 380008 | 114 | 9006 | 1 | -746779066 | Description: _VTO_Baie; CTLG_EXTERNAL_LINK - 1, DocType: 9; 1, Tag: 211; 1, Crc: -732809594; IFC_Pset_Caractéristiques - ID: 380008; Numérotation: 080; Numéro niveau: 03; Titre niveau: Rez-de-chaussée; IFC_Pset_Géométrie_Allège - Hauteur: 0 cm; Stratigraphie: ...; Épaisseur: 0 cm; IFC_Pset_Géométrie_Ébrasement - Présent: yes; Côté supérieur: no; Côté INFÉRIEUR: no; Épaisseur extérieure: 11 cm; Épaisseur latérale gauche: 3 cm; Épaisseur latérale droite: 3 cm; Épiasseur latérale supérieure: 3 cm; Épaisseur diagonale gauche: 0 cm; Épaisseur diagonale droite: 0 cm; Épaisseur diagonale inférieure: 0 cm; Épaisseur diagonale supérieure: 0 cm; Épaisseur intérieur: 0 cm; Données: [a : 110,00; b [gche]: 30,00; b [dte]: 30,00; b [sup]: 30,00; c [gche]: 0,00; c [dte]: 0,00; c [inf]: 0,00; c [sup]: 0,00; d: 0,00] mm; IFC_Pset_Géométrie_Seuil - Type: Aucun; Épaisseur: 0 cm; Épaisseur interne: 0 cm; Décalage séparation: 0 cm; Appui extérieur: 0 cm; Appui intérieur: 0 cm; Côté latéral externe: 0 cm; Côté latéral interne: 0 cm; IFC_Pset_Géométrie_Chambranle - Position: Aucun; Épaisseur Chambranle intérieur: 0 cm; Longueur Chambranle intérieur: 0 cm; Superposition Chambranle intérieur: 0 cm; Épaisseur Intrados: 0 cm; Épaisseur Chambranle extérieur: 0 cm; Largeur Chambranle extérieur: 0 cm; Superposition Chambranle extérieur: 0 cm; Épaisseur Intrados extérieur: 0 cm; Décalage séparation intrados: 0 cm; IFC_Pset_Géométrie_CORNICHE depuis profil - Position: Aucune; sets with these values: 2; IFC_Pset_Géométrie_CORNICHE Extérieure à partir d'un profil - Décalage: 0; Angle: 0 deg; Symétrie: no; Fermer: no; sets with these values: 2; IFC_Pset_Géométrie_BASE Extérieure à partir d'un profil - Angle: 0 deg; Symétrie: no; Côté: 0 cm; sets with these values: 2; IFC_Pset_Géométrie - Côté extérieur: 1; Invertir (dte/gche): no; Invertir (intérieur/extérieur): no; Forme: Arc + Rectangle; Largeur: 130.159 cm; Hauteur: 296.398 cm; Hauteur 2: 0 cm; Rayon Arc: 13.9605 cm; Rayon Cercle: 0 cm; Demi-axe horizontal: 0 cm; Demi-axe vertical: 0 cm; IFC_Pset_Géométrie_GRILLE - décalage: 0 cm; Offset latéral: 0 cm; Décalage supérieur: 0 cm; Décalage inférieur: 0 cm; Nombre accrochages latéraux: 0; Nombre d'accrochages supérieurs: 0; Nombre accrochages inférieurs: 0; IFC_Pset_Géométrie_Niche - Présent: no; Stratigraphie: Paroi en béton armé [120,00]; Épaisseur: 12 cm; Alignement: Intérieur; Décalage: 0 cm; IFC_Pset_Système de Référence Altimétrique_INFÉRIEUR - NIVEAU: Rez-de-chaussée (Rez-de-chaussée 1047); delta: 37.3001 cm; sous Niveau: <aucun>; IFC_Pset_Données Métré - Surface de l'Ouverture: 40100 cm2; Surface de l'Ébrasement: 13200 cm2; Surface du Seuil: 0 cm2; Surface du Seuil intérieur: 0 cm2; Volume du seuil: 0 cm3; Volume du seuil intérieur: 0 cm3; Surface de la Niche: 0 cm2; Surface de la Grille: 0 cm2; Volume de la Grille: 0 cm3
Baie 379602 | Rez-de-chaussée | 379602 | 114 | 9006 | 1 | -746779066 | Description: _VTO_Baie; CTLG_EXTERNAL_LINK - 1, DocType: 9; 1, Tag: 211; 1, Crc: -1554559915; IFC_Pset_Caractéristiques - ID: 379602; Numérotation: 078; Numéro niveau: 03; Titre niveau: Rez-de-chaussée; IFC_Pset_Géométrie_Allège - Hauteur: 0 cm; Stratigraphie: ...; Épaisseur: 0 cm; IFC_Pset_Géométrie_Ébrasement - Présent: yes; Côté supérieur: no; Côté INFÉRIEUR: no; Épaisseur extérieure: 11 cm; Épaisseur latérale gauche: 3 cm; Épaisseur latérale droite: 3 cm; Épiasseur latérale supérieure: 3 cm; Épaisseur diagonale gauche: 0 cm; Épaisseur diagonale droite: 0 cm; Épaisseur diagonale inférieure: 0 cm; Épaisseur diagonale supérieure: 0 cm; Épaisseur intérieur: 0 cm; Données: [a : 110,00; b: 30,00; c: 0,00; d: 0,00] mm; IFC_Pset_Géométrie_Seuil - Type: Aucun; Épaisseur: 0 cm; Épaisseur interne: 0 cm; Décalage séparation: 0 cm; Appui extérieur: 0 cm; Appui intérieur: 0 cm; Côté latéral externe: 0 cm; Côté latéral interne: 0 cm; IFC_Pset_Géométrie_Chambranle - Position: Aucun; Épaisseur Chambranle intérieur: 0 cm; Longueur Chambranle intérieur: 0 cm; Superposition Chambranle intérieur: 0 cm; Épaisseur Intrados: 0 cm; Épaisseur Chambranle extérieur: 0 cm; Largeur Chambranle extérieur: 0 cm; Superposition Chambranle extérieur: 0 cm; Épaisseur Intrados extérieur: 0 cm; Décalage séparation intrados: 0 cm; IFC_Pset_Géométrie_CORNICHE depuis profil - Position: Aucune; sets with these values: 2; IFC_Pset_Géométrie_CORNICHE Extérieure à partir d'un profil - Décalage: 0; Angle: 0 deg; Symétrie: no; Fermer: no; sets with these values: 2; IFC_Pset_Géométrie_BASE Extérieure à partir d'un profil - Angle: 0 deg; Symétrie: no; Côté: 0 cm; sets with these values: 2; IFC_Pset_Géométrie - Côté extérieur: 0; Invertir (dte/gche): no; Invertir (intérieur/extérieur): no; Forme: Rectangle; Largeur: 130.308 cm; Hauteur: 345.766 cm; Hauteur 2: 0 cm; Rayon Arc: 0 cm; Rayon Cercle: 0 cm; Demi-axe horizontal: 0 cm; Demi-axe vertical: 0 cm; IFC_Pset_Géométrie_GRILLE - décalage: 0 cm; Offset latéral: 0 cm; Décalage supérieur: 0 cm; Décalage inférieur: 0 cm; Nombre accrochages latéraux: 0; Nombre d'accrochages supérieurs: 0; Nombre accrochages inférieurs: 0; IFC_Pset_Géométrie_Niche - Présent: no; Stratigraphie: default [80,00]; Épaisseur: 8 cm; Alignement: Intérieur; Décalage: 0 cm; IFC_Pset_Système de Référence Altimétrique_INFÉRIEUR - NIVEAU: Rez-de-chaussée (Rez-de-chaussée 1047); delta: 47.0012 cm; sous Niveau: <aucun>; IFC_Pset_Données Métré - Surface de l'Ouverture: 45100 cm2; Surface de l'Ébrasement: 12400 cm2; Surface du Seuil: 0 cm2; Surface du Seuil intérieur: 0 cm2; Volume du seuil: 0 cm3; Volume du seuil intérieur: 0 cm3; Surface de la Niche: 0 cm2; Surface de la Grille: 0 cm2; Volume de la Grille: 0 cm3
Baie 379601 | Rez-de-chaussée | 379601 | 114 | 9006 | 1 | -746779066 | Description: _VTO_Baie; CTLG_EXTERNAL_LINK - 1, DocType: 9; 1, Tag: 211; 1, Crc: -1554559915; IFC_Pset_Caractéristiques - ID: 379601; Numérotation: 077; Numéro niveau: 03; Titre niveau: Rez-de-chaussée; IFC_Pset_Géométrie_Allège - Hauteur: 0 cm; Stratigraphie: ...; Épaisseur: 0 cm; IFC_Pset_Géométrie_Ébrasement - Présent: yes; Côté supérieur: no; Côté INFÉRIEUR: no; Épaisseur extérieure: 11 cm; Épaisseur latérale gauche: 3 cm; Épaisseur latérale droite: 3 cm; Épiasseur latérale supérieure: 3 cm; Épaisseur diagonale gauche: 0 cm; Épaisseur diagonale droite: 0 cm; Épaisseur diagonale inférieure: 0 cm; Épaisseur diagonale supérieure: 0 cm; Épaisseur intérieur: 0 cm; Données: [a : 110,00; b: 30,00; c: 0,00; d: 0,00] mm; IFC_Pset_Géométrie_Seuil - Type: Aucun; Épaisseur: 0 cm; Épaisseur interne: 0 cm; Décalage séparation: 0 cm; Appui extérieur: 0 cm; Appui intérieur: 0 cm; Côté latéral externe: 0 cm; Côté latéral interne: 0 cm; IFC_Pset_Géométrie_Chambranle - Position: Aucun; Épaisseur Chambranle intérieur: 0 cm; Longueur Chambranle intérieur: 0 cm; Superposition Chambranle intérieur: 0 cm; Épaisseur Intrados: 0 cm; Épaisseur Chambranle extérieur: 0 cm; Largeur Chambranle extérieur: 0 cm; Superposition Chambranle extérieur: 0 cm; Épaisseur Intrados extérieur: 0 cm; Décalage séparation intrados: 0 cm; IFC_Pset_Géométrie_CORNICHE depuis profil - Position: Aucune; sets with these values: 2; IFC_Pset_Géométrie_CORNICHE Extérieure à partir d'un profil - Décalage: 0; Angle: 0 deg; Symétrie: no; Fermer: no; sets with these values: 2; IFC_Pset_Géométrie_BASE Extérieure à partir d'un profil - Angle: 0 deg; Symétrie: no; Côté: 0 cm; sets with these values: 2; IFC_Pset_Géométrie - Côté extérieur: 1; Invertir (dte/gche): no; Invertir (intérieur/extérieur): yes; Forme: Rectangle; Largeur: 130.26 cm; Hauteur: 346.195 cm; Hauteur 2: 0 cm; Rayon Arc: 0 cm; Rayon Cercle: 0 cm; Demi-axe horizontal: 0 cm; Demi-axe vertical: 0 cm; IFC_Pset_Géométrie_GRILLE - décalage: 0 cm; Offset latéral: 0 cm; Décalage supérieur: 0 cm; Décalage inférieur: 0 cm; Nombre accrochages latéraux: 0; Nombre d'accrochages supérieurs: 0; Nombre accrochages inférieurs: 0; IFC_Pset_Géométrie_Niche - Présent: no; Stratigraphie: default [80,00]; Épaisseur: 8 cm; Alignement: Intérieur; Décalage: 0 cm; IFC_Pset_Système de Référence Altimétrique_INFÉRIEUR - NIVEAU: Rez-de-chaussée (Rez-de-chaussée 1047); delta: 47.0139 cm; sous Niveau: <aucun>; IFC_Pset_Données Métré - Surface de l'Ouverture: 45100 cm2; Surface de l'Ébrasement: 12500 cm2; Surface du Seuil: 0 cm2; Surface du Seuil intérieur: 0 cm2; Volume du seuil: 0 cm3; Volume du seuil intérieur: 0 cm3; Surface de la Niche: 0 cm2; Surface de la Grille: 0 cm2; Volume de la Grille: 0 cm3
Baie 379472 | Rez-de-chaussée | 379472 | 114 | 9006 | 1 | -746779066 | Description: _VTO_Baie; CTLG_EXTERNAL_LINK - 1, DocType: 9; 1, Tag: 211; 1, Crc: -1554559915; IFC_Pset_Caractéristiques - ID: 379472; Numérotation: 064; Numéro niveau: 03; Titre niveau: Rez-de-chaussée; IFC_Pset_Géométrie_Allège - Hauteur: 0 cm; Stratigraphie: ...; Épaisseur: 0 cm; IFC_Pset_Géométrie_Ébrasement - Présent: no; Côté supérieur: no; Côté INFÉRIEUR: no; Épaisseur extérieure: 0 cm; Épaisseur latérale gauche: 0 cm; Épaisseur latérale droite: 0 cm; Épiasseur latérale supérieure: 0 cm; Épaisseur diagonale gauche: 0 cm; Épaisseur diagonale droite: 0 cm; Épaisseur diagonale inférieure: 0 cm; Épaisseur diagonale supérieure: 0 cm; Épaisseur intérieur: 0 cm; IFC_Pset_Géométrie_Seuil - Type: Aucun; Épaisseur: 0 cm; Épaisseur interne: 0 cm; Décalage séparation: 0 cm; Appui extérieur: 0 cm; Appui intérieur: 0 cm; Côté latéral externe: 0 cm; Côté latéral interne: 0 cm; IFC_Pset_Géométrie_Chambranle - Position: Aucun; Épaisseur Chambranle intérieur: 0 cm; Longueur Chambranle intérieur: 0 cm; Superposition Chambranle intérieur: 0 cm; Épaisseur Intrados: 0 cm; Épaisseur Chambranle extérieur: 0 cm; Largeur Chambranle extérieur: 0 cm; Superposition Chambranle extérieur: 0 cm; Épaisseur Intrados extérieur: 0 cm; Décalage séparation intrados: 0 cm; IFC_Pset_Géométrie_CORNICHE depuis profil - Position: Aucune; sets with these values: 2; IFC_Pset_Géométrie_CORNICHE Extérieure à partir d'un profil - Décalage: 0; Angle: 0 deg; Symétrie: no; Fermer: no; sets with these values: 2; IFC_Pset_Géométrie_BASE Extérieure à partir d'un profil - Angle: 0 deg; Symétrie: no; Côté: 0 cm; sets with these values: 2; IFC_Pset_Géométrie - Côté extérieur: 0; Invertir (dte/gche): no; Invertir (intérieur/extérieur): no; Forme: Arc + Rectangle; Largeur: 159.596 cm; Hauteur: 342.067 cm; Hauteur 2: 0 cm; Rayon Arc: 23.4926 cm; Rayon Cercle: 0 cm; Demi-axe horizontal: 0 cm; Demi-axe vertical: 0 cm; IFC_Pset_Géométrie_GRILLE - décalage: 0 cm; Offset latéral: 0 cm; Décalage supérieur: 0 cm; Décalage inférieur: 0 cm; Nombre accrochages latéraux: 0; Nombre d'accrochages supérieurs: 0; Nombre accrochages inférieurs: 0; IFC_Pset_Géométrie_Niche - Présent: no; Stratigraphie: default [80,00]; Épaisseur: 8 cm; Alignement: Intérieur; Décalage: 0 cm; IFC_Pset_Système de Référence Altimétrique_INFÉRIEUR - NIVEAU: Rez-de-chaussée (Rez-de-chaussée 1047); delta: 0.0128504 cm; sous Niveau: <aucun>; IFC_Pset_Données Métré - Surface de l'Ouverture: 57100 cm2; Surface de l'Ébrasement: 0 cm2; Surface du Seuil: 0 cm2; Surface du Seuil intérieur: 0 cm2; Volume du seuil: 0 cm3; Volume du seuil intérieur: 0 cm3; Surface de la Niche: 0 cm2; Surface de la Grille: 0 cm2; Volume de la Grille: 0 cm3
Baie 380011 | Rez-de-chaussée | 380011 | 114 | 9006 | 1 | -746779066 | Description: _VTO_Baie; CTLG_EXTERNAL_LINK - 1, DocType: 9; 1, Tag: 211; 1, Crc: -732809594; IFC_Pset_Caractéristiques - ID: 380011; Numérotation: 083; Numéro niveau: 03; Titre niveau: Rez-de-chaussée; IFC_Pset_Géométrie_Allège - Hauteur: 0 cm; Stratigraphie: ...; Épaisseur: 0 cm; IFC_Pset_Géométrie_Ébrasement - Présent: no; Côté supérieur: no; Côté INFÉRIEUR: no; Épaisseur extérieure: 0 cm; Épaisseur latérale gauche: 0 cm; Épaisseur latérale droite: 0 cm; Épiasseur latérale supérieure: 0 cm; Épaisseur diagonale gauche: 0 cm; Épaisseur diagonale droite: 0 cm; Épaisseur diagonale inférieure: 0 cm; Épaisseur diagonale supérieure: 0 cm; Épaisseur intérieur: 0 cm; IFC_Pset_Géométrie_Seuil - Type: Aucun; Épaisseur: 0 cm; Épaisseur interne: 0 cm; Décalage séparation: 0 cm; Appui extérieur: 0 cm; Appui intérieur: 0 cm; Côté latéral externe: 0 cm; Côté latéral interne: 0 cm; IFC_Pset_Géométrie_Chambranle - Position: Aucun; Épaisseur Chambranle intérieur: 0 cm; Longueur Chambranle intérieur: 0 cm; Superposition Chambranle intérieur: 0 cm; Épaisseur Intrados: 0 cm; Épaisseur Chambranle extérieur: 0 cm; Largeur Chambranle extérieur: 0 cm; Superposition Chambranle extérieur: 0 cm; Épaisseur Intrados extérieur: 0 cm; Décalage séparation intrados: 0 cm; IFC_Pset_Géométrie_CORNICHE depuis profil - Position: Aucune; sets with these values: 2; IFC_Pset_Géométrie_CORNICHE Extérieure à partir d'un profil - Décalage: 0; Angle: 0 deg; Symétrie: no; Fermer: no; sets with these values: 2; IFC_Pset_Géométrie_BASE Extérieure à partir d'un profil - Angle: 0 deg; Symétrie: no; Côté: 0 cm; sets with these values: 2; IFC_Pset_Géométrie - Côté extérieur: 1; Invertir (dte/gche): no; Invertir (intérieur/extérieur): no; Forme: Rectangle; Largeur: 92.593 cm; Hauteur: 206.671 cm; Hauteur 2: 0 cm; Rayon Arc: 0 cm; Rayon Cercle: 0 cm; Demi-axe horizontal: 0 cm; Demi-axe vertical: 0 cm; IFC_Pset_Géométrie_GRILLE - décalage: 0 cm; Offset latéral: 0 cm; Décalage supérieur: 0 cm; Décalage inférieur: 0 cm; Nombre accrochages latéraux: 0; Nombre d'accrochages supérieurs: 0; Nombre accrochages inférieurs: 0; IFC_Pset_Géométrie_Niche - Présent: no; Stratigraphie: Paroi en béton armé [120,00]; Épaisseur: 12 cm; Alignement: Intérieur; Décalage: 0 cm; IFC_Pset_Système de Référence Altimétrique_INFÉRIEUR - NIVEAU: Rez-de-chaussée (Rez-de-chaussée 1047); delta: 49.561 cm; sous Niveau: <aucun>; IFC_Pset_Données Métré - Surface de l'Ouverture: 19100 cm2; Surface de l'Ébrasement: 0 cm2; Surface du Seuil: 0 cm2; Surface du Seuil intérieur: 0 cm2; Volume du seuil: 0 cm3; Volume du seuil intérieur: 0 cm3; Surface de la Niche: 0 cm2; Surface de la Grille: 0 cm2; Volume de la Grille: 0 cm3
Baie 379480 | Rez-de-chaussée | 379480 | 114 | 9006 | 1 | -746779066 | Description: _VTO_Baie; CTLG_EXTERNAL_LINK - 1, DocType: 9; 1, Tag: 211; 1, Crc: -1554559915; IFC_Pset_Caractéristiques - ID: 379480; Numérotation: 070; Numéro niveau: 03; Titre niveau: Rez-de-chaussée; IFC_Pset_Géométrie_Allège - Hauteur: 0 cm; Stratigraphie: ...; Épaisseur: 0 cm; IFC_Pset_Géométrie_Ébrasement - Présent: yes; Côté supérieur: no; Côté INFÉRIEUR: no; Épaisseur extérieure: 11 cm; Épaisseur latérale gauche: 3 cm; Épaisseur latérale droite: 3 cm; Épiasseur latérale supérieure: 3 cm; Épaisseur diagonale gauche: 0 cm; Épaisseur diagonale droite: 0 cm; Épaisseur diagonale inférieure: 0 cm; Épaisseur diagonale supérieure: 0 cm; Épaisseur intérieur: 0 cm; Données: [a : 110,00; b: 30,00; c: 0,00; d: 0,00] mm; IFC_Pset_Géométrie_Seuil - Type: Aucun; Épaisseur: 0 cm; Épaisseur interne: 0 cm; Décalage séparation: 0 cm; Appui extérieur: 0 cm; Appui intérieur: 0 cm; Côté latéral externe: 0 cm; Côté latéral interne: 0 cm; IFC_Pset_Géométrie_Chambranle - Position: Aucun; Épaisseur Chambranle intérieur: 0 cm; Longueur Chambranle intérieur: 0 cm; Superposition Chambranle intérieur: 0 cm; Épaisseur Intrados: 0 cm; Épaisseur Chambranle extérieur: 0 cm; Largeur Chambranle extérieur: 0 cm; Superposition Chambranle extérieur: 0 cm; Épaisseur Intrados extérieur: 0 cm; Décalage séparation intrados: 0 cm; IFC_Pset_Géométrie_CORNICHE depuis profil - Position: Aucune; sets with these values: 2; IFC_Pset_Géométrie_CORNICHE Extérieure à partir d'un profil - Décalage: 0; Angle: 0 deg; Symétrie: no; Fermer: no; sets with these values: 2; IFC_Pset_Géométrie_BASE Extérieure à partir d'un profil - Angle: 0 deg; Symétrie: no; Côté: 0 cm; sets with these values: 2; IFC_Pset_Géométrie - Côté extérieur: 0; Invertir (dte/gche): no; Invertir (intérieur/extérieur): no; Forme: Rectangle; Largeur: 129.534 cm; Hauteur: 345.544 cm; Hauteur 2: 0 cm; Rayon Arc: 0 cm; Rayon Cercle: 0 cm; Demi-axe horizontal: 0 cm; Demi-axe vertical: 0 cm; IFC_Pset_Géométrie_GRILLE - décalage: 0 cm; Offset latéral: 0 cm; Décalage supérieur: 0 cm; Décalage inférieur: 0 cm; Nombre accrochages latéraux: 0; Nombre d'accrochages supérieurs: 0; Nombre accrochages inférieurs: 0; IFC_Pset_Géométrie_Niche - Présent: no; Stratigraphie: default [80,00]; Épaisseur: 8 cm; Alignement: Intérieur; Décalage: 0 cm; IFC_Pset_Système de Référence Altimétrique_INFÉRIEUR - NIVEAU: Rez-de-chaussée (Rez-de-chaussée 1047); delta: 48.3991 cm; sous Niveau: <aucun>; IFC_Pset_Données Métré - Surface de l'Ouverture: 44800 cm2; Surface de l'Ébrasement: 12400 cm2; Surface du Seuil: 0 cm2; Surface du Seuil intérieur: 0 cm2; Volume du seuil: 0 cm3; Volume du seuil intérieur: 0 cm3; Surface de la Niche: 0 cm2; Surface de la Grille: 0 cm2; Volume de la Grille: 0 cm3
Baie 379478 | Rez-de-chaussée | 379478 | 114 | 9006 | 1 | -746779066 | Description: _VTO_Baie; CTLG_EXTERNAL_LINK - 1, DocType: 9; 1, Tag: 211; 1, Crc: -1554559915; IFC_Pset_Caractéristiques - ID: 379478; Numérotation: 068; Numéro niveau: 03; Titre niveau: Rez-de-chaussée; IFC_Pset_Géométrie_Allège - Hauteur: 0 cm; Stratigraphie: ...; Épaisseur: 0 cm; IFC_Pset_Géométrie_Ébrasement - Présent: yes; Côté supérieur: no; Côté INFÉRIEUR: no; Épaisseur extérieure: 11 cm; Épaisseur latérale gauche: 3 cm; Épaisseur latérale droite: 3 cm; Épiasseur latérale supérieure: 3 cm; Épaisseur diagonale gauche: 0 cm; Épaisseur diagonale droite: 0 cm; Épaisseur diagonale inférieure: 0 cm; Épaisseur diagonale supérieure: 0 cm; Épaisseur intérieur: 0 cm; Données: [a : 110,00; b: 30,00; c: 0,00; d: 0,00] mm; IFC_Pset_Géométrie_Seuil - Type: Aucun; Épaisseur: 0 cm; Épaisseur interne: 0 cm; Décalage séparation: 0 cm; Appui extérieur: 0 cm; Appui intérieur: 0 cm; Côté latéral externe: 0 cm; Côté latéral interne: 0 cm; IFC_Pset_Géométrie_Chambranle - Position: Aucun; Épaisseur Chambranle intérieur: 0 cm; Longueur Chambranle intérieur: 0 cm; Superposition Chambranle intérieur: 0 cm; Épaisseur Intrados: 0 cm; Épaisseur Chambranle extérieur: 0 cm; Largeur Chambranle extérieur: 0 cm; Superposition Chambranle extérieur: 0 cm; Épaisseur Intrados extérieur: 0 cm; Décalage séparation intrados: 0 cm; IFC_Pset_Géométrie_CORNICHE depuis profil - Position: Aucune; sets with these values: 2; IFC_Pset_Géométrie_CORNICHE Extérieure à partir d'un profil - Décalage: 0; Angle: 0 deg; Symétrie: no; Fermer: no; sets with these values: 2; IFC_Pset_Géométrie_BASE Extérieure à partir d'un profil - Angle: 0 deg; Symétrie: no; Côté: 0 cm; sets with these values: 2; IFC_Pset_Géométrie - Côté extérieur: 0; Invertir (dte/gche): no; Invertir (intérieur/extérieur): no; Forme: Rectangle; Largeur: 130.071 cm; Hauteur: 345.105 cm; Hauteur 2: 0 cm; Rayon Arc: 0 cm; Rayon Cercle: 0 cm; Demi-axe horizontal: 0 cm; Demi-axe vertical: 0 cm; IFC_Pset_Géométrie_GRILLE - décalage: 0 cm; Offset latéral: 0 cm; Décalage supérieur: 0 cm; Décalage inférieur: 0 cm; Nombre accrochages latéraux: 0; Nombre d'accrochages supérieurs: 0; Nombre accrochages inférieurs: 0; IFC_Pset_Géométrie_Niche - Présent: no; Stratigraphie: default [80,00]; Épaisseur: 8 cm; Alignement: Intérieur; Décalage: 0 cm; IFC_Pset_Système de Référence Altimétrique_INFÉRIEUR - NIVEAU: Rez-de-chaussée (Rez-de-chaussée 1047); delta: 48.3 cm; sous Niveau: <aucun>; IFC_Pset_Données Métré - Surface de l'Ouverture: 44900 cm2; Surface de l'Ébrasement: 12400 cm2; Surface du Seuil: 0 cm2; Surface du Seuil intérieur: 0 cm2; Volume du seuil: 0 cm3; Volume du seuil intérieur: 0 cm3; Surface de la Niche: 0 cm2; Surface de la Grille: 0 cm2; Volume de la Grille: 0 cm3
Baie 379479 | Rez-de-chaussée | 379479 | 114 | 9006 | 1 | -746779066 | Description: _VTO_Baie; CTLG_EXTERNAL_LINK - 1, DocType: 9; 1, Tag: 211; 1, Crc: -1554559915; IFC_Pset_Caractéristiques - ID: 379479; Numérotation: 069; Numéro niveau: 03; Titre niveau: Rez-de-chaussée; IFC_Pset_Géométrie_Allège - Hauteur: 0 cm; Stratigraphie: ...; Épaisseur: 0 cm; IFC_Pset_Géométrie_Ébrasement - Présent: yes; Côté supérieur: no; Côté INFÉRIEUR: no; Épaisseur extérieure: 11 cm; Épaisseur latérale gauche: 3 cm; Épaisseur latérale droite: 3 cm; Épiasseur latérale supérieure: 3 cm; Épaisseur diagonale gauche: 0 cm; Épaisseur diagonale droite: 0 cm; Épaisseur diagonale inférieure: 0 cm; Épaisseur diagonale supérieure: 0 cm; Épaisseur intérieur: 0 cm; Données: [a : 110,00; b: 30,00; c: 0,00; d: 0,00] mm; IFC_Pset_Géométrie_Seuil - Type: Aucun; Épaisseur: 0 cm; Épaisseur interne: 0 cm; Décalage séparation: 0 cm; Appui extérieur: 0 cm; Appui intérieur: 0 cm; Côté latéral externe: 0 cm; Côté latéral interne: 0 cm; IFC_Pset_Géométrie_Chambranle - Position: Aucun; Épaisseur Chambranle intérieur: 0 cm; Longueur Chambranle intérieur: 0 cm; Superposition Chambranle intérieur: 0 cm; Épaisseur Intrados: 0 cm; Épaisseur Chambranle extérieur: 0 cm; Largeur Chambranle extérieur: 0 cm; Superposition Chambranle extérieur: 0 cm; Épaisseur Intrados extérieur: 0 cm; Décalage séparation intrados: 0 cm; IFC_Pset_Géométrie_CORNICHE depuis profil - Position: Aucune; sets with these values: 2; IFC_Pset_Géométrie_CORNICHE Extérieure à partir d'un profil - Décalage: 0; Angle: 0 deg; Symétrie: no; Fermer: no; sets with these values: 2; IFC_Pset_Géométrie_BASE Extérieure à partir d'un profil - Angle: 0 deg; Symétrie: no; Côté: 0 cm; sets with these values: 2; IFC_Pset_Géométrie - Côté extérieur: 0; Invertir (dte/gche): no; Invertir (intérieur/extérieur): no; Forme: Rectangle; Largeur: 129.828 cm; Hauteur: 345.427 cm; Hauteur 2: 0 cm; Rayon Arc: 0 cm; Rayon Cercle: 0 cm; Demi-axe horizontal: 0 cm; Demi-axe vertical: 0 cm; IFC_Pset_Géométrie_GRILLE - décalage: 0 cm; Offset latéral: 0 cm; Décalage supérieur: 0 cm; Décalage inférieur: 0 cm; Nombre accrochages latéraux: 0; Nombre d'accrochages supérieurs: 0; Nombre accrochages inférieurs: 0; IFC_Pset_Géométrie_Niche - Présent: no; Stratigraphie: default [80,00]; Épaisseur: 8 cm; Alignement: Intérieur; Décalage: 0 cm; IFC_Pset_Système de Référence Altimétrique_INFÉRIEUR - NIVEAU: Rez-de-chaussée (Rez-de-chaussée 1047); delta: 47.9601 cm; sous Niveau: <aucun>; IFC_Pset_Données Métré - Surface de l'Ouverture: 44800 cm2; Surface de l'Ébrasement: 12400 cm2; Surface du Seuil: 0 cm2; Surface du Seuil intérieur: 0 cm2; Volume du seuil: 0 cm3; Volume du seuil intérieur: 0 cm3; Surface de la Niche: 0 cm2; Surface de la Grille: 0 cm2; Volume de la Grille: 0 cm3
Baie 379477 | Rez-de-chaussée | 379477 | 114 | 9006 | 1 | -746779066 | Description: _VTO_Baie; CTLG_EXTERNAL_LINK - 1, DocType: 9; 1, Tag: 211; 1, Crc: -1554559915; IFC_Pset_Caractéristiques - ID: 379477; Numérotation: 067; Numéro niveau: 03; Titre niveau: Rez-de-chaussée; IFC_Pset_Géométrie_Allège - Hauteur: 0 cm; Stratigraphie: ...; Épaisseur: 0 cm; IFC_Pset_Géométrie_Ébrasement - Présent: yes; Côté supérieur: no; Côté INFÉRIEUR: no; Épaisseur extérieure: 11 cm; Épaisseur latérale gauche: 3 cm; Épaisseur latérale droite: 3 cm; Épiasseur latérale supérieure: 3 cm; Épaisseur diagonale gauche: 0 cm; Épaisseur diagonale droite: 0 cm; Épaisseur diagonale inférieure: 0 cm; Épaisseur diagonale supérieure: 0 cm; Épaisseur intérieur: 0 cm; Données: [a : 110,00; b: 30,00; c: 0,00; d: 0,00] mm; IFC_Pset_Géométrie_Seuil - Type: Aucun; Épaisseur: 0 cm; Épaisseur interne: 0 cm; Décalage séparation: 0 cm; Appui extérieur: 0 cm; Appui intérieur: 0 cm; Côté latéral externe: 0 cm; Côté latéral interne: 0 cm; IFC_Pset_Géométrie_Chambranle - Position: Aucun; Épaisseur Chambranle intérieur: 0 cm; Longueur Chambranle intérieur: 0 cm; Superposition Chambranle intérieur: 0 cm; Épaisseur Intrados: 0 cm; Épaisseur Chambranle extérieur: 0 cm; Largeur Chambranle extérieur: 0 cm; Superposition Chambranle extérieur: 0 cm; Épaisseur Intrados extérieur: 0 cm; Décalage séparation intrados: 0 cm; IFC_Pset_Géométrie_CORNICHE depuis profil - Position: Aucune; sets with these values: 2; IFC_Pset_Géométrie_CORNICHE Extérieure à partir d'un profil - Décalage: 0; Angle: 0 deg; Symétrie: no; Fermer: no; sets with these values: 2; IFC_Pset_Géométrie_BASE Extérieure à partir d'un profil - Angle: 0 deg; Symétrie: no; Côté: 0 cm; sets with these values: 2; IFC_Pset_Géométrie - Côté extérieur: 0; Invertir (dte/gche): no; Invertir (intérieur/extérieur): no; Forme: Rectangle; Largeur: 129.761 cm; Hauteur: 362.101 cm; Hauteur 2: 0 cm; Rayon Arc: 0 cm; Rayon Cercle: 0 cm; Demi-axe horizontal: 0 cm; Demi-axe vertical: 0 cm; IFC_Pset_Géométrie_GRILLE - décalage: 0 cm; Offset latéral: 0 cm; Décalage supérieur: 0 cm; Décalage inférieur: 0 cm; Nombre accrochages latéraux: 0; Nombre d'accrochages supérieurs: 0; Nombre accrochages inférieurs: 0; IFC_Pset_Géométrie_Niche - Présent: no; Stratigraphie: default [80,00]; Épaisseur: 8 cm; Alignement: Intérieur; Décalage: 0 cm; IFC_Pset_Système de Référence Altimétrique_INFÉRIEUR - NIVEAU: Rez-de-chaussée (Rez-de-chaussée 1047); delta: 31 cm; sous Niveau: <aucun>; IFC_Pset_Données Métré - Surface de l'Ouverture: 47000 cm2; Surface de l'Ébrasement: 13000 cm2; Surface du Seuil: 0 cm2; Surface du Seuil intérieur: 0 cm2; Volume du seuil: 0 cm3; Volume du seuil intérieur: 0 cm3; Surface de la Niche: 0 cm2; Surface de la Grille: 0 cm2; Volume de la Grille: 0 cm3
Baie 379470 | Rez-de-chaussée | 379470 | 114 | 9006 | 1 | -746779066 | Description: _VTO_Baie; CTLG_EXTERNAL_LINK - 1, DocType: 9; 1, Tag: 211; 1, Crc: -1554559915; IFC_Pset_Caractéristiques - ID: 379470; Numérotation: 062; Numéro niveau: 03; Titre niveau: Rez-de-chaussée; IFC_Pset_Géométrie_Allège - Hauteur: 0 cm; Stratigraphie: ...; Épaisseur: 0 cm; IFC_Pset_Géométrie_Ébrasement - Présent: no; Côté supérieur: no; Côté INFÉRIEUR: no; Épaisseur extérieure: 0 cm; Épaisseur latérale gauche: 0 cm; Épaisseur latérale droite: 0 cm; Épiasseur latérale supérieure: 0 cm; Épaisseur diagonale gauche: 0 cm; Épaisseur diagonale droite: 0 cm; Épaisseur diagonale inférieure: 0 cm; Épaisseur diagonale supérieure: 0 cm; Épaisseur intérieur: 0 cm; IFC_Pset_Géométrie_Seuil - Type: Aucun; Épaisseur: 0 cm; Épaisseur interne: 0 cm; Décalage séparation: 0 cm; Appui extérieur: 0 cm; Appui intérieur: 0 cm; Côté latéral externe: 0 cm; Côté latéral interne: 0 cm; IFC_Pset_Géométrie_Chambranle - Position: Aucun; Épaisseur Chambranle intérieur: 0 cm; Longueur Chambranle intérieur: 0 cm; Superposition Chambranle intérieur: 0 cm; Épaisseur Intrados: 0 cm; Épaisseur Chambranle extérieur: 0 cm; Largeur Chambranle extérieur: 0 cm; Superposition Chambranle extérieur: 0 cm; Épaisseur Intrados extérieur: 0 cm; Décalage séparation intrados: 0 cm; IFC_Pset_Géométrie_CORNICHE depuis profil - Position: Aucune; sets with these values: 2; IFC_Pset_Géométrie_CORNICHE Extérieure à partir d'un profil - Décalage: 0; Angle: 0 deg; Symétrie: no; Fermer: no; sets with these values: 2; IFC_Pset_Géométrie_BASE Extérieure à partir d'un profil - Angle: 0 deg; Symétrie: no; Côté: 0 cm; sets with these values: 2; IFC_Pset_Géométrie - Côté extérieur: 0; Invertir (dte/gche): no; Invertir (intérieur/extérieur): no; Forme: Arc + Rectangle; Largeur: 359.627 cm; Hauteur: 364.203 cm; Hauteur 2: 0 cm; Rayon Arc: 43.2126 cm; Rayon Cercle: 0 cm; Demi-axe horizontal: 0 cm; Demi-axe vertical: 0 cm; IFC_Pset_Géométrie_GRILLE - décalage: 0 cm; Offset latéral: 0 cm; Décalage supérieur: 0 cm; Décalage inférieur: 0 cm; Nombre accrochages latéraux: 0; Nombre d'accrochages supérieurs: 0; Nombre accrochages inférieurs: 0; IFC_Pset_Géométrie_Niche - Présent: no; Stratigraphie: default [80,00]; Épaisseur: 8 cm; Alignement: Intérieur; Décalage: 0 cm; IFC_Pset_Système de Référence Altimétrique_INFÉRIEUR - NIVEAU: Rez-de-chaussée (Rez-de-chaussée 1047); delta: -20 cm; sous Niveau: <aucun>; IFC_Pset_Données Métré - Surface de l'Ouverture: 141300 cm2; Surface de l'Ébrasement: 0 cm2; Surface du Seuil: 0 cm2; Surface du Seuil intérieur: 0 cm2; Volume du seuil: 0 cm3; Volume du seuil intérieur: 0 cm3; Surface de la Niche: 0 cm2; Surface de la Grille: 0 cm2; Volume de la Grille: 0 cm3
Baie 427150 | Rez-de-chaussée | 427150 | 114 | 9006 | 1 | -746779066 | Description: _VTO_Baie; CTLG_EXTERNAL_LINK - 1, DocType: 9; 1, Tag: 211; 1, Crc: -732809594; IFC_Pset_Caractéristiques - ID: 427150; Numérotation: 094; Numéro niveau: 03; Titre niveau: Rez-de-chaussée; IFC_Pset_Géométrie_Allège - Hauteur: 0 cm; Stratigraphie: ...; Épaisseur: 0 cm; IFC_Pset_Géométrie_Ébrasement - Présent: no; Côté supérieur: no; Côté INFÉRIEUR: no; Épaisseur extérieure: 0 cm; Épaisseur latérale gauche: 0 cm; Épaisseur latérale droite: 0 cm; Épiasseur latérale supérieure: 0 cm; Épaisseur diagonale gauche: 0 cm; Épaisseur diagonale droite: 0 cm; Épaisseur diagonale inférieure: 0 cm; Épaisseur diagonale supérieure: 0 cm; Épaisseur intérieur: 0 cm; IFC_Pset_Géométrie_Seuil - Type: Aucun; Épaisseur: 0 cm; Épaisseur interne: 0 cm; Décalage séparation: 0 cm; Appui extérieur: 0 cm; Appui intérieur: 0 cm; Côté latéral externe: 0 cm; Côté latéral interne: 0 cm; IFC_Pset_Géométrie_Chambranle - Position: Aucun; Épaisseur Chambranle intérieur: 0 cm; Longueur Chambranle intérieur: 0 cm; Superposition Chambranle intérieur: 0 cm; Épaisseur Intrados: 0 cm; Épaisseur Chambranle extérieur: 0 cm; Largeur Chambranle extérieur: 0 cm; Superposition Chambranle extérieur: 0 cm; Épaisseur Intrados extérieur: 0 cm; Décalage séparation intrados: 0 cm; IFC_Pset_Géométrie_CORNICHE depuis profil - Position: Aucune; sets with these values: 2; IFC_Pset_Géométrie_CORNICHE Extérieure à partir d'un profil - Décalage: 0; Angle: 0 deg; Symétrie: no; Fermer: no; sets with these values: 2; IFC_Pset_Géométrie_BASE Extérieure à partir d'un profil - Angle: 0 deg; Symétrie: no; Côté: 0 cm; sets with these values: 2; IFC_Pset_Géométrie - Côté extérieur: 0; Invertir (dte/gche): no; Invertir (intérieur/extérieur): no; Forme: Rectangle; Largeur: 100.474 cm; Hauteur: 472.102 cm; Hauteur 2: 0 cm; Rayon Arc: 0 cm; Rayon Cercle: 0 cm; Demi-axe horizontal: 0 cm; Demi-axe vertical: 0 cm; IFC_Pset_Géométrie_GRILLE - décalage: 0 cm; Offset latéral: 0 cm; Décalage supérieur: 0 cm; Décalage inférieur: 0 cm; Nombre accrochages latéraux: 0; Nombre d'accrochages supérieurs: 0; Nombre accrochages inférieurs: 0; IFC_Pset_Géométrie_Niche - Présent: no; Stratigraphie: Paroi en béton armé [120,00]; Épaisseur: 12 cm; Alignement: Intérieur; Décalage: 0 cm; IFC_Pset_Système de Référence Altimétrique_INFÉRIEUR - NIVEAU: Rez-de-chaussée (Rez-de-chaussée 1047); delta: 297.172 cm; sous Niveau: <aucun>; IFC_Pset_Données Métré - Surface de l'Ouverture: 47400 cm2; Surface de l'Ébrasement: 0 cm2; Surface du Seuil: 0 cm2; Surface du Seuil intérieur: 0 cm2; Volume du seuil: 0 cm3; Volume du seuil intérieur: 0 cm3; Surface de la Niche: 0 cm2; Surface de la Grille: 0 cm2; Volume de la Grille: 0 cm3
Baie 427149 | Rez-de-chaussée | 427149 | 114 | 9006 | 1 | -746779066 | Description: _VTO_Baie; CTLG_EXTERNAL_LINK - 1, DocType: 9; 1, Tag: 211; 1, Crc: -732809594; IFC_Pset_Caractéristiques - ID: 427149; Numérotation: 093; Numéro niveau: 03; Titre niveau: Rez-de-chaussée; IFC_Pset_Géométrie_Allège - Hauteur: 0 cm; Stratigraphie: ...; Épaisseur: 0 cm; IFC_Pset_Géométrie_Ébrasement - Présent: no; Côté supérieur: no; Côté INFÉRIEUR: no; Épaisseur extérieure: 0 cm; Épaisseur latérale gauche: 0 cm; Épaisseur latérale droite: 0 cm; Épiasseur latérale supérieure: 0 cm; Épaisseur diagonale gauche: 0 cm; Épaisseur diagonale droite: 0 cm; Épaisseur diagonale inférieure: 0 cm; Épaisseur diagonale supérieure: 0 cm; Épaisseur intérieur: 0 cm; IFC_Pset_Géométrie_Seuil - Type: Aucun; Épaisseur: 0 cm; Épaisseur interne: 0 cm; Décalage séparation: 0 cm; Appui extérieur: 0 cm; Appui intérieur: 0 cm; Côté latéral externe: 0 cm; Côté latéral interne: 0 cm; IFC_Pset_Géométrie_Chambranle - Position: Aucun; Épaisseur Chambranle intérieur: 0 cm; Longueur Chambranle intérieur: 0 cm; Superposition Chambranle intérieur: 0 cm; Épaisseur Intrados: 0 cm; Épaisseur Chambranle extérieur: 0 cm; Largeur Chambranle extérieur: 0 cm; Superposition Chambranle extérieur: 0 cm; Épaisseur Intrados extérieur: 0 cm; Décalage séparation intrados: 0 cm; IFC_Pset_Géométrie_CORNICHE depuis profil - Position: Aucune; sets with these values: 2; IFC_Pset_Géométrie_CORNICHE Extérieure à partir d'un profil - Décalage: 0; Angle: 0 deg; Symétrie: no; Fermer: no; sets with these values: 2; IFC_Pset_Géométrie_BASE Extérieure à partir d'un profil - Angle: 0 deg; Symétrie: no; Côté: 0 cm; sets with these values: 2; IFC_Pset_Géométrie - Côté extérieur: 0; Invertir (dte/gche): no; Invertir (intérieur/extérieur): no; Forme: Rectangle; Largeur: 100.308 cm; Hauteur: 472.306 cm; Hauteur 2: 0 cm; Rayon Arc: 0 cm; Rayon Cercle: 0 cm; Demi-axe horizontal: 0 cm; Demi-axe vertical: 0 cm; IFC_Pset_Géométrie_GRILLE - décalage: 0 cm; Offset latéral: 0 cm; Décalage supérieur: 0 cm; Décalage inférieur: 0 cm; Nombre accrochages latéraux: 0; Nombre d'accrochages supérieurs: 0; Nombre accrochages inférieurs: 0; IFC_Pset_Géométrie_Niche - Présent: no; Stratigraphie: Paroi en béton armé [120,00]; Épaisseur: 12 cm; Alignement: Intérieur; Décalage: 0 cm; IFC_Pset_Système de Référence Altimétrique_INFÉRIEUR - NIVEAU: Rez-de-chaussée (Rez-de-chaussée 1047); delta: 297.695 cm; sous Niveau: <aucun>; IFC_Pset_Données Métré - Surface de l'Ouverture: 47400 cm2; Surface de l'Ébrasement: 0 cm2; Surface du Seuil: 0 cm2; Surface du Seuil intérieur: 0 cm2; Volume du seuil: 0 cm3; Volume du seuil intérieur: 0 cm3; Surface de la Niche: 0 cm2; Surface de la Grille: 0 cm2; Volume de la Grille: 0 cm3
Baie 379471 | Rez-de-chaussée | 379471 | 114 | 9006 | 1 | -746779066 | Description: _VTO_Baie; CTLG_EXTERNAL_LINK - 1, DocType: 9; 1, Tag: 211; 1, Crc: -1554559915; IFC_Pset_Caractéristiques - ID: 379471; Numérotation: 063; Numéro niveau: 03; Titre niveau: Rez-de-chaussée; IFC_Pset_Géométrie_Allège - Hauteur: 0 cm; Stratigraphie: ...; Épaisseur: 0 cm; IFC_Pset_Géométrie_Ébrasement - Présent: no; Côté supérieur: no; Côté INFÉRIEUR: no; Épaisseur extérieure: 0 cm; Épaisseur latérale gauche: 0 cm; Épaisseur latérale droite: 0 cm; Épiasseur latérale supérieure: 0 cm; Épaisseur diagonale gauche: 0 cm; Épaisseur diagonale droite: 0 cm; Épaisseur diagonale inférieure: 0 cm; Épaisseur diagonale supérieure: 0 cm; Épaisseur intérieur: 0 cm; IFC_Pset_Géométrie_Seuil - Type: Aucun; Épaisseur: 0 cm; Épaisseur interne: 0 cm; Décalage séparation: 0 cm; Appui extérieur: 0 cm; Appui intérieur: 0 cm; Côté latéral externe: 0 cm; Côté latéral interne: 0 cm; IFC_Pset_Géométrie_Chambranle - Position: Aucun; Épaisseur Chambranle intérieur: 0 cm; Longueur Chambranle intérieur: 0 cm; Superposition Chambranle intérieur: 0 cm; Épaisseur Intrados: 0 cm; Épaisseur Chambranle extérieur: 0 cm; Largeur Chambranle extérieur: 0 cm; Superposition Chambranle extérieur: 0 cm; Épaisseur Intrados extérieur: 0 cm; Décalage séparation intrados: 0 cm; IFC_Pset_Géométrie_CORNICHE depuis profil - Position: Aucune; sets with these values: 2; IFC_Pset_Géométrie_CORNICHE Extérieure à partir d'un profil - Décalage: 0; Angle: 0 deg; Symétrie: no; Fermer: no; sets with these values: 2; IFC_Pset_Géométrie_BASE Extérieure à partir d'un profil - Angle: 0 deg; Symétrie: no; Côté: 0 cm; sets with these values: 2; IFC_Pset_Géométrie - Côté extérieur: 0; Invertir (dte/gche): no; Invertir (intérieur/extérieur): no; Forme: Arc + Rectangle; Largeur: 159.596 cm; Hauteur: 342.067 cm; Hauteur 2: 0 cm; Rayon Arc: 23.4926 cm; Rayon Cercle: 0 cm; Demi-axe horizontal: 0 cm; Demi-axe vertical: 0 cm; IFC_Pset_Géométrie_GRILLE - décalage: 0 cm; Offset latéral: 0 cm; Décalage supérieur: 0 cm; Décalage inférieur: 0 cm; Nombre accrochages latéraux: 0; Nombre d'accrochages supérieurs: 0; Nombre accrochages inférieurs: 0; IFC_Pset_Géométrie_Niche - Présent: no; Stratigraphie: default [80,00]; Épaisseur: 8 cm; Alignement: Intérieur; Décalage: 0 cm; IFC_Pset_Système de Référence Altimétrique_INFÉRIEUR - NIVEAU: Rez-de-chaussée (Rez-de-chaussée 1047); delta: -1.3743 cm; sous Niveau: <aucun>; IFC_Pset_Données Métré - Surface de l'Ouverture: 57100 cm2; Surface de l'Ébrasement: 0 cm2; Surface du Seuil: 0 cm2; Surface du Seuil intérieur: 0 cm2; Volume du seuil: 0 cm3; Volume du seuil intérieur: 0 cm3; Surface de la Niche: 0 cm2; Surface de la Grille: 0 cm2; Volume de la Grille: 0 cm3
4294966461_11 | Rez-de-chaussée | -835 | 2002 | 2002 | 0 | -1292786862
4294966380_11 | Rez-de-chaussée | -916 | 2002 | 2002 | 0 | -1292786862
4294966462_11 | Rez-de-chaussée | -834 | 2002 | 2002 | 0 | -1292786862
Baie 1527283 | Rez-de-chaussée | 1527283 | 114 | 9006 | 1 | -746779066 | Description: _VTO_Baie; CTLG_EXTERNAL_LINK - 1, DocType: 9; 1, Tag: 211; 1, Crc: -1554559915; IFC_Pset_Caractéristiques - ID: 1527283; Numérotation: 168; Numéro niveau: 03; Titre niveau: Rez-de-chaussée; IFC_Pset_Géométrie_Allège - Hauteur: 0 cm; Stratigraphie: ...; Épaisseur: 0 cm; IFC_Pset_Géométrie_Ébrasement - Présent: no; Côté supérieur: no; Côté INFÉRIEUR: no; Épaisseur extérieure: 0 cm; Épaisseur latérale gauche: 0 cm; Épaisseur latérale droite: 0 cm; Épiasseur latérale supérieure: 0 cm; Épaisseur diagonale gauche: 0 cm; Épaisseur diagonale droite: 0 cm; Épaisseur diagonale inférieure: 0 cm; Épaisseur diagonale supérieure: 0 cm; Épaisseur intérieur: 0 cm; IFC_Pset_Géométrie_Seuil - Type: Aucun; Épaisseur: 0 cm; Épaisseur interne: 0 cm; Décalage séparation: 0 cm; Appui extérieur: 0 cm; Appui intérieur: 0 cm; Côté latéral externe: 0 cm; Côté latéral interne: 0 cm; IFC_Pset_Géométrie_Chambranle - Position: Aucun; Épaisseur Chambranle intérieur: 0 cm; Longueur Chambranle intérieur: 0 cm; Superposition Chambranle intérieur: 0 cm; Épaisseur Intrados: 0 cm; Épaisseur Chambranle extérieur: 0 cm; Largeur Chambranle extérieur: 0 cm; Superposition Chambranle extérieur: 0 cm; Épaisseur Intrados extérieur: 0 cm; Décalage séparation intrados: 0 cm; IFC_Pset_Géométrie_CORNICHE depuis profil - Position: Aucune; sets with these values: 2; IFC_Pset_Géométrie_CORNICHE Extérieure à partir d'un profil - Décalage: 0; Angle: 0 deg; Symétrie: no; Fermer: no; sets with these values: 2; IFC_Pset_Géométrie_BASE Extérieure à partir d'un profil - Angle: 0 deg; Symétrie: no; Côté: 0 cm; sets with these values: 2; IFC_Pset_Géométrie - Côté extérieur: 0; Invertir (dte/gche): no; Invertir (intérieur/extérieur): no; Forme: Rectangle; Largeur: 165.996 cm; Hauteur: 221.6 cm; Hauteur 2: 0 cm; Rayon Arc: 0 cm; Rayon Cercle: 0 cm; Demi-axe horizontal: 0 cm; Demi-axe vertical: 0 cm; IFC_Pset_Géométrie_GRILLE - décalage: 0 cm; Offset latéral: 0 cm; Décalage supérieur: 0 cm; Décalage inférieur: 0 cm; Nombre accrochages latéraux: 0; Nombre d'accrochages supérieurs: 0; Nombre accrochages inférieurs: 0; IFC_Pset_Géométrie_Niche - Présent: no; Stratigraphie: default [80,00]; Épaisseur: 8 cm; Alignement: Intérieur; Décalage: 0 cm; IFC_Pset_Système de Référence Altimétrique_INFÉRIEUR - NIVEAU: Rez-de-chaussée (Rez-de-chaussée 1047); delta: 0.0128504 cm; sous Niveau: <aucun>; IFC_Pset_Données Métré - Surface de l'Ouverture: 36800 cm2; Surface de l'Ébrasement: 0 cm2; Surface du Seuil: 0 cm2; Surface du Seuil intérieur: 0 cm2; Volume du seuil: 0 cm3; Volume du seuil intérieur: 0 cm3; Surface de la Niche: 0 cm2; Surface de la Grille: 0 cm2; Volume de la Grille: 0 cm3
4294966482_11 | Rez-de-chaussée | -814 | 2002 | 2002 | 0 | -1292786862
4294966481_11 | Rez-de-chaussée | -815 | 2002 | 2002 | 0 | -1292786862
4294966483_11 | Rez-de-chaussée | -813 | 2002 | 2002 | 0 | -1292786862
4294966480_11 | Rez-de-chaussée | -816 | 2002 | 2002 | 0 | -1292786862
4294966351_11 | Rez-de-chaussée | -945 | 2002 | 2002 | 0 | -1292786862
4294966382_11 | Rez-de-chaussée | -914 | 2002 | 2002 | 0 | -1292786862
4294966509_11 | Rez-de-chaussée | -787 | 2002 | 2002 | 0 | -1292786862
4294966454_11 | Rez-de-chaussée | -842 | 2002 | 2002 | 0 | -1292786862
4294966448_11 | Rez-de-chaussée | -848 | 2002 | 2002 | 0 | -1292786862
4294966453_11 | Rez-de-chaussée | -843 | 2002 | 2002 | 0 | -1292786862
4294966449_11 | Rez-de-chaussée | -847 | 2002 | 2002 | 0 | -1292786862
4294966460_11 | Rez-de-chaussée | -836 | 2002 | 2002 | 0 | -1292786862
4294966459_11 | Rez-de-chaussée | -837 | 2002 | 2002 | 0 | -1292786862
4294966447_11 | Rez-de-chaussée | -849 | 2002 | 2002 | 0 | -1292786862
4294966450_11 | Rez-de-chaussée | -846 | 2002 | 2002 | 0 | -1292786862
4294966463_11 | Rez-de-chaussée | -833 | 2002 | 2002 | 0 | -1292786862
4294966451_11 | Rez-de-chaussée | -845 | 2002 | 2002 | 0 | -1292786862
4294966457_11 | Rez-de-chaussée | -839 | 2002 | 2002 | 0 | -1292786862
4294966496_11 | Rez-de-chaussée | -800 | 2002 | 2002 | 0 | -1292786862
Baie 722380 | Rez-de-chaussée | 722380 | 114 | 9006 | 1 | -746779066 | Description: _VTO_Baie; CTLG_EXTERNAL_LINK - 1, DocType: 9; 1, Tag: 211; 1, Crc: -732809594; IFC_Pset_Caractéristiques - ID: 722380; Numérotation: 136; Numéro niveau: 03; Titre niveau: Rez-de-chaussée; IFC_Pset_Géométrie_Allège - Hauteur: 0 cm; Stratigraphie: ...; Épaisseur: 0 cm; IFC_Pset_Géométrie_Ébrasement - Présent: yes; Côté supérieur: no; Côté INFÉRIEUR: no; Épaisseur extérieure: 17 cm; Épaisseur latérale gauche: 3 cm; Épaisseur latérale droite: 3 cm; Épiasseur latérale supérieure: 3 cm; Épaisseur diagonale gauche: 0 cm; Épaisseur diagonale droite: 0 cm; Épaisseur diagonale inférieure: 0 cm; Épaisseur diagonale supérieure: 0 cm; Épaisseur intérieur: 0 cm; Données: [a : 170,00; b: 30,00; c: 0,00; d: 0,00] mm; IFC_Pset_Géométrie_Seuil - Type: Aucun; Épaisseur: 0 cm; Épaisseur interne: 0 cm; Décalage séparation: 0 cm; Appui extérieur: 0 cm; Appui intérieur: 0 cm; Côté latéral externe: 0 cm; Côté latéral interne: 0 cm; IFC_Pset_Géométrie_Chambranle - Position: Aucun; Épaisseur Chambranle intérieur: 0 cm; Longueur Chambranle intérieur: 0 cm; Superposition Chambranle intérieur: 0 cm; Épaisseur Intrados: 0 cm; Épaisseur Chambranle extérieur: 0 cm; Largeur Chambranle extérieur: 0 cm; Superposition Chambranle extérieur: 0 cm; Épaisseur Intrados extérieur: 0 cm; Décalage séparation intrados: 0 cm; IFC_Pset_Géométrie_CORNICHE depuis profil - Position: Aucune; sets with these values: 2; IFC_Pset_Géométrie_CORNICHE Extérieure à partir d'un profil - Décalage: 0; Angle: 0 deg; Symétrie: no; Fermer: no; sets with these values: 2; IFC_Pset_Géométrie_BASE Extérieure à partir d'un profil - Angle: 0 deg; Symétrie: no; Côté: 0 cm; sets with these values: 2; IFC_Pset_Géométrie - Côté extérieur: 0; Invertir (dte/gche): no; Invertir (intérieur/extérieur): no; Forme: Rectangle; Largeur: 99.6942 cm; Hauteur: 210.89 cm; Hauteur 2: 0 cm; Rayon Arc: 0 cm; Rayon Cercle: 0 cm; Demi-axe horizontal: 0 cm; Demi-axe vertical: 0 cm; IFC_Pset_Géométrie_GRILLE - décalage: 0 cm; Offset latéral: 0 cm; Décalage supérieur: 0 cm; Décalage inférieur: 0 cm; Nombre accrochages latéraux: 0; Nombre d'accrochages supérieurs: 0; Nombre accrochages inférieurs: 0; IFC_Pset_Géométrie_Niche - Présent: no; Stratigraphie: Paroi en béton armé [120,00]; Épaisseur: 12 cm; Alignement: Intérieur; Décalage: 0 cm; IFC_Pset_Système de Référence Altimétrique_INFÉRIEUR - NIVEAU: Rez-de-chaussée (Rez-de-chaussée 1047); delta: 0.0128504 cm; sous Niveau: <aucun>; IFC_Pset_Données Métré - Surface de l'Ouverture: 21000 cm2; Surface de l'Ébrasement: 9900 cm2; Surface du Seuil: 0 cm2; Surface du Seuil intérieur: 0 cm2; Volume du seuil: 0 cm3; Volume du seuil intérieur: 0 cm3; Surface de la Niche: 0 cm2; Surface de la Grille: 0 cm2; Volume de la Grille: 0 cm3
4294966352_11 | Rez-de-chaussée | -944 | 2002 | 2002 | 0 | -1292786862
4294966452_11 | Rez-de-chaussée | -844 | 2002 | 2002 | 0 | -1292786862
Baie 45359 | Rez-de-chaussée | 45359 | 114 | 9006 | 1 | -746779066 | Description: _VTO_Baie; CTLG_EXTERNAL_LINK - 1, DocType: 9; 1, Tag: 211; 1, Crc: 1051879175; IFC_Pset_Caractéristiques - ID: 45359; Numérotation: 018; Numéro niveau: 03; Titre niveau: Rez-de-chaussée; IFC_Pset_Géométrie_Allège - Hauteur: 0 cm; Stratigraphie: ...; Épaisseur: 0 cm; IFC_Pset_Géométrie_Ébrasement - Présent: no; Côté supérieur: no; Côté INFÉRIEUR: no; Épaisseur extérieure: 0 cm; Épaisseur latérale gauche: 0 cm; Épaisseur latérale droite: 0 cm; Épiasseur latérale supérieure: 0 cm; Épaisseur diagonale gauche: 0 cm; Épaisseur diagonale droite: 0 cm; Épaisseur diagonale inférieure: 0 cm; Épaisseur diagonale supérieure: 0 cm; Épaisseur intérieur: 0 cm; IFC_Pset_Géométrie_Seuil - Type: Aucun; Épaisseur: 0 cm; Épaisseur interne: 0 cm; Décalage séparation: 0 cm; Appui extérieur: 0 cm; Appui intérieur: 0 cm; Côté latéral externe: 0 cm; Côté latéral interne: 0 cm; IFC_Pset_Géométrie_Chambranle - Position: Aucun; Épaisseur Chambranle intérieur: 0 cm; Longueur Chambranle intérieur: 0 cm; Superposition Chambranle intérieur: 0 cm; Épaisseur Intrados: 0 cm; Épaisseur Chambranle extérieur: 0 cm; Largeur Chambranle extérieur: 0 cm; Superposition Chambranle extérieur: 0 cm; Épaisseur Intrados extérieur: 0 cm; Décalage séparation intrados: 0 cm; IFC_Pset_Géométrie_CORNICHE depuis profil - Position: Aucune; sets with these values: 2; IFC_Pset_Géométrie_CORNICHE Extérieure à partir d'un profil - Décalage: 0; Angle: 0 deg; Symétrie: no; Fermer: no; sets with these values: 2; IFC_Pset_Géométrie_BASE Extérieure à partir d'un profil - Angle: 0 deg; Symétrie: no; Côté: 0 cm; sets with these values: 2; IFC_Pset_Géométrie - Côté extérieur: 1; Invertir (dte/gche): no; Invertir (intérieur/extérieur): no; Forme: Arc + Rectangle; Largeur: 185.981 cm; Hauteur: 40 cm; Hauteur 2: 0 cm; Rayon Arc: 68.0773 cm; Rayon Cercle: 0 cm; Demi-axe horizontal: 0 cm; Demi-axe vertical: 0 cm; IFC_Pset_Géométrie_GRILLE - décalage: 0 cm; Offset latéral: 0 cm; Décalage supérieur: 0 cm; Décalage inférieur: 0 cm; Nombre accrochages latéraux: 0; Nombre d'accrochages supérieurs: 0; Nombre accrochages inférieurs: 0; IFC_Pset_Géométrie_Niche - Présent: no; Stratigraphie: default [42,86]; Épaisseur: 4.286 cm; Alignement: Intérieur; Décalage: 0 cm; IFC_Pset_Système de Référence Altimétrique_INFÉRIEUR - NIVEAU: Rez-de-chaussée (Rez-de-chaussée 1047); delta: 235 cm; sous Niveau: <aucun>; IFC_Pset_Données Métré - Surface de l'Ouverture: 16700 cm2; Surface de l'Ébrasement: 0 cm2; Surface du Seuil: 0 cm2; Surface du Seuil intérieur: 0 cm2; Volume du seuil: 0 cm3; Volume du seuil intérieur: 0 cm3; Surface de la Niche: 0 cm2; Surface de la Grille: 0 cm2; Volume de la Grille: 0 cm3
4294966348_11 | Rez-de-chaussée | -948 | 2002 | 2002 | 0 | -1292786862
4294966343_11 | Rez-de-chaussée | -953 | 2002 | 2002 | 0 | -1292786862
Baie 30037 | Rez-de-chaussée | 30037 | 114 | 9006 | 1 | -746779066 | Description: _VTO_Baie; CTLG_EXTERNAL_LINK - 1, DocType: 9; 1, Tag: 211; 1, Crc: 1582870039; IFC_Pset_Caractéristiques - ID: 30037; Numérotation: 007; Numéro niveau: 03; Titre niveau: Rez-de-chaussée; IFC_Pset_Géométrie_Allège - Hauteur: 0 cm; Stratigraphie: ...; Épaisseur: 0 cm; IFC_Pset_Géométrie_Ébrasement - Présent: no; Côté supérieur: no; Côté INFÉRIEUR: no; Épaisseur extérieure: 0 cm; Épaisseur latérale gauche: 0 cm; Épaisseur latérale droite: 0 cm; Épiasseur latérale supérieure: 0 cm; Épaisseur diagonale gauche: 0 cm; Épaisseur diagonale droite: 0 cm; Épaisseur diagonale inférieure: 0 cm; Épaisseur diagonale supérieure: 0 cm; Épaisseur intérieur: 0 cm; IFC_Pset_Géométrie_Seuil - Type: Aucun; Épaisseur: 0 cm; Épaisseur interne: 0 cm; Décalage séparation: 0 cm; Appui extérieur: 0 cm; Appui intérieur: 0 cm; Côté latéral externe: 0 cm; Côté latéral interne: 0 cm; IFC_Pset_Géométrie_Chambranle - Position: Aucun; Épaisseur Chambranle intérieur: 0 cm; Longueur Chambranle intérieur: 0 cm; Superposition Chambranle intérieur: 0 cm; Épaisseur Intrados: 0 cm; Épaisseur Chambranle extérieur: 0 cm; Largeur Chambranle extérieur: 0 cm; Superposition Chambranle extérieur: 0 cm; Épaisseur Intrados extérieur: 0 cm; Décalage séparation intrados: 0 cm; IFC_Pset_Géométrie_CORNICHE depuis profil - Position: Aucune; sets with these values: 2; IFC_Pset_Géométrie_CORNICHE Extérieure à partir d'un profil - Décalage: 0; Angle: 0 deg; Symétrie: no; Fermer: no; sets with these values: 2; IFC_Pset_Géométrie_BASE Extérieure à partir d'un profil - Angle: 0 deg; Symétrie: no; Côté: 0 cm; sets with these values: 2; IFC_Pset_Géométrie - Côté extérieur: 0; Invertir (dte/gche): no; Invertir (intérieur/extérieur): no; Forme: Rectangle; Largeur: 127.547 cm; Hauteur: 267 cm; Hauteur 2: 0 cm; Rayon Arc: 0 cm; Rayon Cercle: 0 cm; Demi-axe horizontal: 0 cm; Demi-axe vertical: 0 cm; IFC_Pset_Géométrie_GRILLE - décalage: 0 cm; Offset latéral: 0 cm; Décalage supérieur: 0 cm; Décalage inférieur: 0 cm; Nombre accrochages latéraux: 0; Nombre d'accrochages supérieurs: 0; Nombre accrochages inférieurs: 0; IFC_Pset_Géométrie_Niche - Présent: no; Stratigraphie: default [210,00]; Épaisseur: 21 cm; Alignement: Intérieur; Décalage: 0 cm; IFC_Pset_Système de Référence Altimétrique_INFÉRIEUR - NIVEAU: Rez-de-chaussée (Rez-de-chaussée 1047); delta: 0.0128504 cm; sous Niveau: <aucun>; IFC_Pset_Données Métré - Surface de l'Ouverture: 34100 cm2; Surface de l'Ébrasement: 0 cm2; Surface du Seuil: 0 cm2; Surface du Seuil intérieur: 0 cm2; Volume du seuil: 0 cm3; Volume du seuil intérieur: 0 cm3; Surface de la Niche: 0 cm2; Surface de la Grille: 0 cm2; Volume de la Grille: 0 cm3
Baie 30036 | Rez-de-chaussée | 30036 | 114 | 9006 | 1 | -746779066 | Description: _VTO_Baie; CTLG_EXTERNAL_LINK - 1, DocType: 9; 1, Tag: 211; 1, Crc: 1582870039; IFC_Pset_Caractéristiques - ID: 30036; Numérotation: 006; Numéro niveau: 03; Titre niveau: Rez-de-chaussée; IFC_Pset_Géométrie_Allège - Hauteur: 0 cm; Stratigraphie: ...; Épaisseur: 0 cm; IFC_Pset_Géométrie_Ébrasement - Présent: no; Côté supérieur: no; Côté INFÉRIEUR: no; Épaisseur extérieure: 0 cm; Épaisseur latérale gauche: 0 cm; Épaisseur latérale droite: 0 cm; Épiasseur latérale supérieure: 0 cm; Épaisseur diagonale gauche: 0 cm; Épaisseur diagonale droite: 0 cm; Épaisseur diagonale inférieure: 0 cm; Épaisseur diagonale supérieure: 0 cm; Épaisseur intérieur: 0 cm; IFC_Pset_Géométrie_Seuil - Type: Aucun; Épaisseur: 0 cm; Épaisseur interne: 0 cm; Décalage séparation: 0 cm; Appui extérieur: 0 cm; Appui intérieur: 0 cm; Côté latéral externe: 0 cm; Côté latéral interne: 0 cm; IFC_Pset_Géométrie_Chambranle - Position: Aucun; Épaisseur Chambranle intérieur: 0 cm; Longueur Chambranle intérieur: 0 cm; Superposition Chambranle intérieur: 0 cm; Épaisseur Intrados: 0 cm; Épaisseur Chambranle extérieur: 0 cm; Largeur Chambranle extérieur: 0 cm; Superposition Chambranle extérieur: 0 cm; Épaisseur Intrados extérieur: 0 cm; Décalage séparation intrados: 0 cm; IFC_Pset_Géométrie_CORNICHE depuis profil - Position: Aucune; sets with these values: 2; IFC_Pset_Géométrie_CORNICHE Extérieure à partir d'un profil - Décalage: 0; Angle: 0 deg; Symétrie: no; Fermer: no; sets with these values: 2; IFC_Pset_Géométrie_BASE Extérieure à partir d'un profil - Angle: 0 deg; Symétrie: no; Côté: 0 cm; sets with these values: 2; IFC_Pset_Géométrie - Côté extérieur: 0; Invertir (dte/gche): no; Invertir (intérieur/extérieur): no; Forme: Rectangle; Largeur: 139.135 cm; Hauteur: 267 cm; Hauteur 2: 0 cm; Rayon Arc: 0 cm; Rayon Cercle: 0 cm; Demi-axe horizontal: 0 cm; Demi-axe vertical: 0 cm; IFC_Pset_Géométrie_GRILLE - décalage: 0 cm; Offset latéral: 0 cm; Décalage supérieur: 0 cm; Décalage inférieur: 0 cm; Nombre accrochages latéraux: 0; Nombre d'accrochages supérieurs: 0; Nombre accrochages inférieurs: 0; IFC_Pset_Géométrie_Niche - Présent: no; Stratigraphie: default [210,00]; Épaisseur: 21 cm; Alignement: Intérieur; Décalage: 0 cm; IFC_Pset_Système de Référence Altimétrique_INFÉRIEUR - NIVEAU: Rez-de-chaussée (Rez-de-chaussée 1047); delta: 0.0128504 cm; sous Niveau: <aucun>; IFC_Pset_Données Métré - Surface de l'Ouverture: 37100 cm2; Surface de l'Ébrasement: 0 cm2; Surface du Seuil: 0 cm2; Surface du Seuil intérieur: 0 cm2; Volume du seuil: 0 cm3; Volume du seuil intérieur: 0 cm3; Surface de la Niche: 0 cm2; Surface de la Grille: 0 cm2; Volume de la Grille: 0 cm3
Baie 30035 | Rez-de-chaussée | 30035 | 114 | 9006 | 1 | -746779066 | Description: _VTO_Baie; CTLG_EXTERNAL_LINK - 1, DocType: 9; 1, Tag: 211; 1, Crc: 1582870039; IFC_Pset_Caractéristiques - ID: 30035; Numérotation: 005; Numéro niveau: 03; Titre niveau: Rez-de-chaussée; IFC_Pset_Géométrie_Allège - Hauteur: 0 cm; Stratigraphie: ...; Épaisseur: 0 cm; IFC_Pset_Géométrie_Ébrasement - Présent: no; Côté supérieur: no; Côté INFÉRIEUR: no; Épaisseur extérieure: 0 cm; Épaisseur latérale gauche: 0 cm; Épaisseur latérale droite: 0 cm; Épiasseur latérale supérieure: 0 cm; Épaisseur diagonale gauche: 0 cm; Épaisseur diagonale droite: 0 cm; Épaisseur diagonale inférieure: 0 cm; Épaisseur diagonale supérieure: 0 cm; Épaisseur intérieur: 0 cm; IFC_Pset_Géométrie_Seuil - Type: Aucun; Épaisseur: 0 cm; Épaisseur interne: 0 cm; Décalage séparation: 0 cm; Appui extérieur: 0 cm; Appui intérieur: 0 cm; Côté latéral externe: 0 cm; Côté latéral interne: 0 cm; IFC_Pset_Géométrie_Chambranle - Position: Aucun; Épaisseur Chambranle intérieur: 0 cm; Longueur Chambranle intérieur: 0 cm; Superposition Chambranle intérieur: 0 cm; Épaisseur Intrados: 0 cm; Épaisseur Chambranle extérieur: 0 cm; Largeur Chambranle extérieur: 0 cm; Superposition Chambranle extérieur: 0 cm; Épaisseur Intrados extérieur: 0 cm; Décalage séparation intrados: 0 cm; IFC_Pset_Géométrie_CORNICHE depuis profil - Position: Aucune; sets with these values: 2; IFC_Pset_Géométrie_CORNICHE Extérieure à partir d'un profil - Décalage: 0; Angle: 0 deg; Symétrie: no; Fermer: no; sets with these values: 2; IFC_Pset_Géométrie_BASE Extérieure à partir d'un profil - Angle: 0 deg; Symétrie: no; Côté: 0 cm; sets with these values: 2; IFC_Pset_Géométrie - Côté extérieur: 0; Invertir (dte/gche): no; Invertir (intérieur/extérieur): no; Forme: Rectangle; Largeur: 127.547 cm; Hauteur: 267 cm; Hauteur 2: 0 cm; Rayon Arc: 0 cm; Rayon Cercle: 0 cm; Demi-axe horizontal: 0 cm; Demi-axe vertical: 0 cm; IFC_Pset_Géométrie_GRILLE - décalage: 0 cm; Offset latéral: 0 cm; Décalage supérieur: 0 cm; Décalage inférieur: 0 cm; Nombre accrochages latéraux: 0; Nombre d'accrochages supérieurs: 0; Nombre accrochages inférieurs: 0; IFC_Pset_Géométrie_Niche - Présent: no; Stratigraphie: default [210,00]; Épaisseur: 21 cm; Alignement: Intérieur; Décalage: 0 cm; IFC_Pset_Système de Référence Altimétrique_INFÉRIEUR - NIVEAU: Rez-de-chaussée (Rez-de-chaussée 1047); delta: 0.0128504 cm; sous Niveau: <aucun>; IFC_Pset_Données Métré - Surface de l'Ouverture: 34100 cm2; Surface de l'Ébrasement: 0 cm2; Surface du Seuil: 0 cm2; Surface du Seuil intérieur: 0 cm2; Volume du seuil: 0 cm3; Volume du seuil intérieur: 0 cm3; Surface de la Niche: 0 cm2; Surface de la Grille: 0 cm2; Volume de la Grille: 0 cm3
4294966353_11 | Rez-de-chaussée | -943 | 2002 | 2002 | 0 | -1292786862
4294966363_11 | Rez-de-chaussée | -933 | 2002 | 2002 | 0 | -1292786862
4294966344_11 | Rez-de-chaussée | -952 | 2002 | 2002 | 0 | -1292786862
4294966345_11 | Rez-de-chaussée | -951 | 2002 | 2002 | 0 | -1292786862
4294966458_11 | Rez-de-chaussée | -838 | 2002 | 2002 | 0 | -1292786862
4294966455_11 | Rez-de-chaussée | -841 | 2002 | 2002 | 0 | -1292786862
4294966350_11 | Rez-de-chaussée | -946 | 2002 | 2002 | 0 | -1292786862
4294966456_11 | Rez-de-chaussée | -840 | 2002 | 2002 | 0 | -1292786862
4294966362_11 | Rez-de-chaussée | -934 | 2002 | 2002 | 0 | -1292786862
4294966365_11 | Rez-de-chaussée | -931 | 2002 | 2002 | 0 | -1292786862
4294966354_11 | Rez-de-chaussée | -942 | 2002 | 2002 | 0 | -1292786862
Baie 379476 | Rez-de-chaussée | 379476 | 114 | 9006 | 1 | -746779066 | Description: _VTO_Baie; CTLG_EXTERNAL_LINK - 1, DocType: 9; 1, Tag: 211; 1, Crc: -1554559915; IFC_Pset_Caractéristiques - ID: 379476; Numérotation: 066; Numéro niveau: 03; Titre niveau: Rez-de-chaussée; IFC_Pset_Géométrie_Allège - Hauteur: 0 cm; Stratigraphie: ...; Épaisseur: 0 cm; IFC_Pset_Géométrie_Ébrasement - Présent: yes; Côté supérieur: no; Côté INFÉRIEUR: no; Épaisseur extérieure: 11 cm; Épaisseur latérale gauche: 3 cm; Épaisseur latérale droite: 3 cm; Épiasseur latérale supérieure: 3 cm; Épaisseur diagonale gauche: 0 cm; Épaisseur diagonale droite: 0 cm; Épaisseur diagonale inférieure: 0 cm; Épaisseur diagonale supérieure: 0 cm; Épaisseur intérieur: 0 cm; Données: [a : 110,00; b: 30,00; c: 0,00; d: 0,00] mm; IFC_Pset_Géométrie_Seuil - Type: Aucun; Épaisseur: 0 cm; Épaisseur interne: 0 cm; Décalage séparation: 0 cm; Appui extérieur: 0 cm; Appui intérieur: 0 cm; Côté latéral externe: 0 cm; Côté latéral interne: 0 cm; IFC_Pset_Géométrie_Chambranle - Position: Aucun; Épaisseur Chambranle intérieur: 0 cm; Longueur Chambranle intérieur: 0 cm; Superposition Chambranle intérieur: 0 cm; Épaisseur Intrados: 0 cm; Épaisseur Chambranle extérieur: 0 cm; Largeur Chambranle extérieur: 0 cm; Superposition Chambranle extérieur: 0 cm; Épaisseur Intrados extérieur: 0 cm; Décalage séparation intrados: 0 cm; IFC_Pset_Géométrie_CORNICHE depuis profil - Position: Aucune; sets with these values: 2; IFC_Pset_Géométrie_CORNICHE Extérieure à partir d'un profil - Décalage: 0; Angle: 0 deg; Symétrie: no; Fermer: no; sets with these values: 2; IFC_Pset_Géométrie_BASE Extérieure à partir d'un profil - Angle: 0 deg; Symétrie: no; Côté: 0 cm; sets with these values: 2; IFC_Pset_Géométrie - Côté extérieur: 0; Invertir (dte/gche): no; Invertir (intérieur/extérieur): no; Forme: Rectangle; Largeur: 129.923 cm; Hauteur: 342.067 cm; Hauteur 2: 0 cm; Rayon Arc: 0 cm; Rayon Cercle: 0 cm; Demi-axe horizontal: 0 cm; Demi-axe vertical: 0 cm; IFC_Pset_Géométrie_GRILLE - décalage: 0 cm; Offset latéral: 0 cm; Décalage supérieur: 0 cm; Décalage inférieur: 0 cm; Nombre accrochages latéraux: 0; Nombre d'accrochages supérieurs: 0; Nombre accrochages inférieurs: 0; IFC_Pset_Géométrie_Niche - Présent: no; Stratigraphie: default [80,00]; Épaisseur: 8 cm; Alignement: Intérieur; Décalage: 0 cm; IFC_Pset_Système de Référence Altimétrique_INFÉRIEUR - NIVEAU: Rez-de-chaussée (Rez-de-chaussée 1047); delta: 47.1701 cm; sous Niveau: <aucun>; IFC_Pset_Données Métré - Surface de l'Ouverture: 44400 cm2; Surface de l'Ébrasement: 12300 cm2; Surface du Seuil: 0 cm2; Surface du Seuil intérieur: 0 cm2; Volume du seuil: 0 cm3; Volume du seuil intérieur: 0 cm3; Surface de la Niche: 0 cm2; Surface de la Grille: 0 cm2; Volume de la Grille: 0 cm3
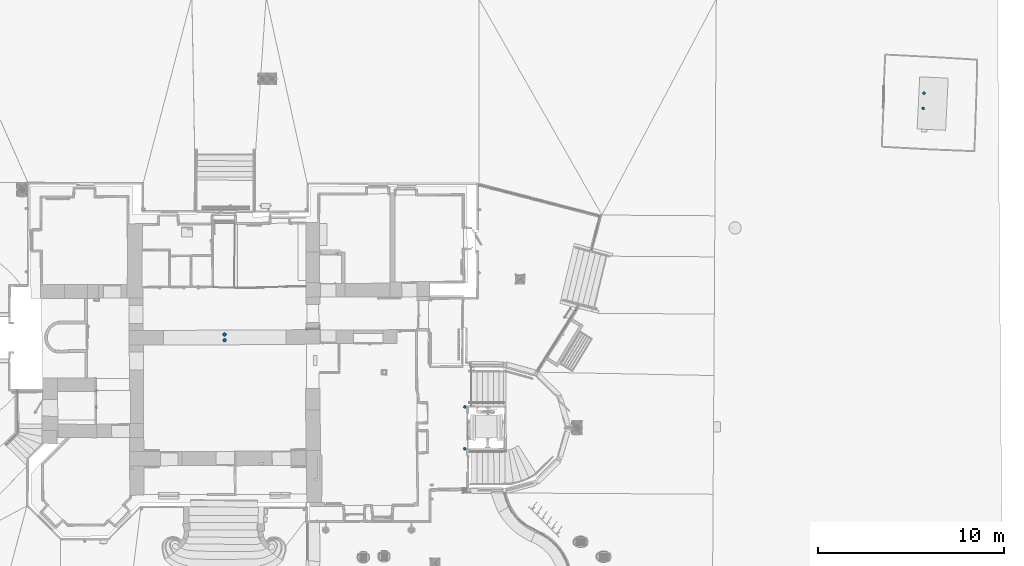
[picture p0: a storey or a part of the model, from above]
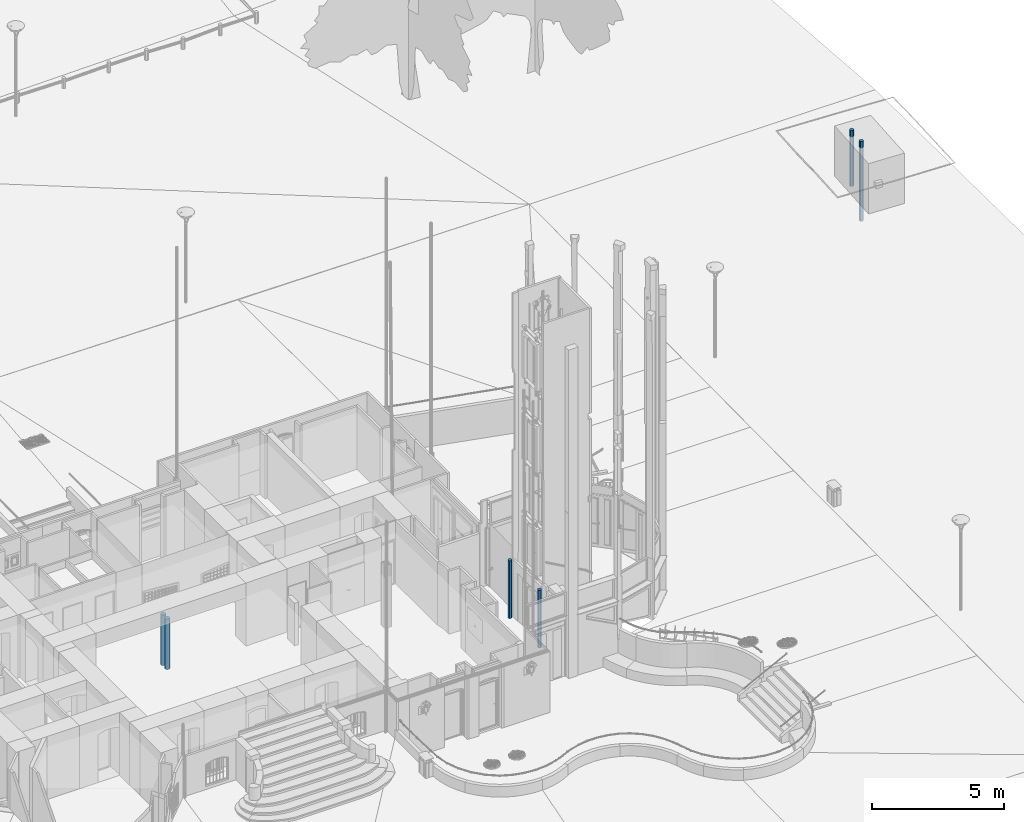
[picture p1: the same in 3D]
Properties of the parts of a building model (IFC2X3), part 12 of 37

# IfcOpeningElement: Opening (367)
Name | In | __RECOGNIZE__, ID | TPLG | TPLG_OD | GENERATE | 0, Crc
Baie 379475 | Rez-de-chaussée | 379475 | 114 | 9006 | 1 | -746779066 | Description: _VTO_Baie; CTLG_EXTERNAL_LINK - 1, DocType: 9; 1, Tag: 211; 1, Crc: -1554559915; IFC_Pset_Caractéristiques - ID: 379475; Numérotation: 065; Numéro niveau: 03; Titre niveau: Rez-de-chaussée; IFC_Pset_Géométrie_Allège - Hauteur: 0 cm; Stratigraphie: ...; Épaisseur: 0 cm; IFC_Pset_Géométrie_Ébrasement - Présent: yes; Côté supérieur: no; Côté INFÉRIEUR: no; Épaisseur extérieure: 11 cm; Épaisseur latérale gauche: 3 cm; Épaisseur latérale droite: 3 cm; Épiasseur latérale supérieure: 3 cm; Épaisseur diagonale gauche: 0 cm; Épaisseur diagonale droite: 0 cm; Épaisseur diagonale inférieure: 0 cm; Épaisseur diagonale supérieure: 0 cm; Épaisseur intérieur: 0 cm; Données: [a : 110,00; b: 30,00; c: 0,00; d: 0,00] mm; IFC_Pset_Géométrie_Seuil - Type: Aucun; Épaisseur: 0 cm; Épaisseur interne: 0 cm; Décalage séparation: 0 cm; Appui extérieur: 0 cm; Appui intérieur: 0 cm; Côté latéral externe: 0 cm; Côté latéral interne: 0 cm; IFC_Pset_Géométrie_Chambranle - Position: Aucun; Épaisseur Chambranle intérieur: 0 cm; Longueur Chambranle intérieur: 0 cm; Superposition Chambranle intérieur: 0 cm; Épaisseur Intrados: 0 cm; Épaisseur Chambranle extérieur: 0 cm; Largeur Chambranle extérieur: 0 cm; Superposition Chambranle extérieur: 0 cm; Épaisseur Intrados extérieur: 0 cm; Décalage séparation intrados: 0 cm; IFC_Pset_Géométrie_CORNICHE depuis profil - Position: Aucune; sets with these values: 2; IFC_Pset_Géométrie_CORNICHE Extérieure à partir d'un profil - Décalage: 0; Angle: 0 deg; Symétrie: no; Fermer: no; sets with these values: 2; IFC_Pset_Géométrie_BASE Extérieure à partir d'un profil - Angle: 0 deg; Symétrie: no; Côté: 0 cm; sets with these values: 2; IFC_Pset_Géométrie - Côté extérieur: 0; Invertir (dte/gche): no; Invertir (intérieur/extérieur): no; Forme: Rectangle; Largeur: 130.421 cm; Hauteur: 345.201 cm; Hauteur 2: 0 cm; Rayon Arc: 0 cm; Rayon Cercle: 0 cm; Demi-axe horizontal: 0 cm; Demi-axe vertical: 0 cm; IFC_Pset_Géométrie_GRILLE - décalage: 0 cm; Offset latéral: 0 cm; Décalage supérieur: 0 cm; Décalage inférieur: 0 cm; Nombre accrochages latéraux: 0; Nombre d'accrochages supérieurs: 0; Nombre accrochages inférieurs: 0; IFC_Pset_Géométrie_Niche - Présent: no; Stratigraphie: default [80,00]; Épaisseur: 8 cm; Alignement: Intérieur; Décalage: 0 cm; IFC_Pset_Système de Référence Altimétrique_INFÉRIEUR - NIVEAU: Rez-de-chaussée (Rez-de-chaussée 1047); delta: 44.4743 cm; sous Niveau: <aucun>; IFC_Pset_Données Métré - Surface de l'Ouverture: 45000 cm2; Surface de l'Ébrasement: 12400 cm2; Surface du Seuil: 0 cm2; Surface du Seuil intérieur: 0 cm2; Volume du seuil: 0 cm3; Volume du seuil intérieur: 0 cm3; Surface de la Niche: 0 cm2; Surface de la Grille: 0 cm2; Volume de la Grille: 0 cm3
4294966361_11 | Rez-de-chaussée | -935 | 2002 | 2002 | 0 | -1292786862
4294966349_11 | Rez-de-chaussée | -947 | 2002 | 2002 | 0 | -1292786862
Baie 719130 | Rez-de-chaussée | 719130 | 114 | 9006 | 1 | -746779066 | Description: _VTO_Baie; CTLG_EXTERNAL_LINK - 1, DocType: 9; 1, Tag: 211; 1, Crc: -732809594; IFC_Pset_Caractéristiques - ID: 719130; Numérotation: 135; Numéro niveau: 03; Titre niveau: Rez-de-chaussée; IFC_Pset_Géométrie_Allège - Hauteur: 0 cm; Stratigraphie: ...; Épaisseur: 0 cm; IFC_Pset_Géométrie_Ébrasement - Présent: yes; Côté supérieur: no; Côté INFÉRIEUR: no; Épaisseur extérieure: 10.5 cm; Épaisseur latérale gauche: 3 cm; Épaisseur latérale droite: 3 cm; Épiasseur latérale supérieure: 3 cm; Épaisseur diagonale gauche: 0 cm; Épaisseur diagonale droite: 0 cm; Épaisseur diagonale inférieure: 0 cm; Épaisseur diagonale supérieure: 0 cm; Épaisseur intérieur: 0 cm; Données: [a : 105,00; b: 30,00; c: 0,00; d: 0,00] mm; IFC_Pset_Géométrie_Seuil - Type: Aucun; Épaisseur: 0 cm; Épaisseur interne: 0 cm; Décalage séparation: 0 cm; Appui extérieur: 0 cm; Appui intérieur: 0 cm; Côté latéral externe: 0 cm; Côté latéral interne: 0 cm; IFC_Pset_Géométrie_Chambranle - Position: Aucun; Épaisseur Chambranle intérieur: 0 cm; Longueur Chambranle intérieur: 0 cm; Superposition Chambranle intérieur: 0 cm; Épaisseur Intrados: 0 cm; Épaisseur Chambranle extérieur: 0 cm; Largeur Chambranle extérieur: 0 cm; Superposition Chambranle extérieur: 0 cm; Épaisseur Intrados extérieur: 0 cm; Décalage séparation intrados: 0 cm; IFC_Pset_Géométrie_CORNICHE depuis profil - Position: Aucune; sets with these values: 2; IFC_Pset_Géométrie_CORNICHE Extérieure à partir d'un profil - Décalage: 0; Angle: 0 deg; Symétrie: no; Fermer: no; sets with these values: 2; IFC_Pset_Géométrie_BASE Extérieure à partir d'un profil - Angle: 0 deg; Symétrie: no; Côté: 0 cm; sets with these values: 2; IFC_Pset_Géométrie - Côté extérieur: 0; Invertir (dte/gche): no; Invertir (intérieur/extérieur): no; Forme: Rectangle; Largeur: 129.428 cm; Hauteur: 390.78 cm; Hauteur 2: 0 cm; Rayon Arc: 0 cm; Rayon Cercle: 0 cm; Demi-axe horizontal: 0 cm; Demi-axe vertical: 0 cm; IFC_Pset_Géométrie_GRILLE - décalage: 0 cm; Offset latéral: 0 cm; Décalage supérieur: 0 cm; Décalage inférieur: 0 cm; Nombre accrochages latéraux: 0; Nombre d'accrochages supérieurs: 0; Nombre accrochages inférieurs: 0; IFC_Pset_Géométrie_Niche - Présent: no; Stratigraphie: Paroi en béton armé [120,00]; Épaisseur: 12 cm; Alignement: Intérieur; Décalage: 0 cm; IFC_Pset_Système de Référence Altimétrique_INFÉRIEUR - NIVEAU: Rez-de-chaussée (Rez-de-chaussée 1047); delta: 0.0128504 cm; sous Niveau: <aucun>; IFC_Pset_Données Métré - Surface de l'Ouverture: 50600 cm2; Surface de l'Ébrasement: 14100 cm2; Surface du Seuil: 0 cm2; Surface du Seuil intérieur: 0 cm2; Volume du seuil: 0 cm3; Volume du seuil intérieur: 0 cm3; Surface de la Niche: 0 cm2; Surface de la Grille: 0 cm2; Volume de la Grille: 0 cm3
Baie 42133 | Rez-de-chaussée | 42133 | 114 | 9006 | 1 | -746779066 | Description: _VTO_Baie; CTLG_EXTERNAL_LINK - 1, DocType: 9; 1, Tag: 211; 1, Crc: 2019374073; IFC_Pset_Caractéristiques - ID: 42133; Numérotation: 017; Numéro niveau: 03; Titre niveau: Rez-de-chaussée; IFC_Pset_Géométrie_Allège - Hauteur: 0 cm; Stratigraphie: ...; Épaisseur: 0 cm; IFC_Pset_Géométrie_Ébrasement - Présent: no; Côté supérieur: no; Côté INFÉRIEUR: no; Épaisseur extérieure: 0 cm; Épaisseur latérale gauche: 0 cm; Épaisseur latérale droite: 0 cm; Épiasseur latérale supérieure: 0 cm; Épaisseur diagonale gauche: 0 cm; Épaisseur diagonale droite: 0 cm; Épaisseur diagonale inférieure: 0 cm; Épaisseur diagonale supérieure: 0 cm; Épaisseur intérieur: 0 cm; IFC_Pset_Géométrie_Seuil - Type: Aucun; Épaisseur: 0 cm; Épaisseur interne: 0 cm; Décalage séparation: 0 cm; Appui extérieur: 0 cm; Appui intérieur: 0 cm; Côté latéral externe: 0 cm; Côté latéral interne: 0 cm; IFC_Pset_Géométrie_Chambranle - Position: Aucun; Épaisseur Chambranle intérieur: 0 cm; Longueur Chambranle intérieur: 0 cm; Superposition Chambranle intérieur: 0 cm; Épaisseur Intrados: 0 cm; Épaisseur Chambranle extérieur: 0 cm; Largeur Chambranle extérieur: 0 cm; Superposition Chambranle extérieur: 0 cm; Épaisseur Intrados extérieur: 0 cm; Décalage séparation intrados: 0 cm; IFC_Pset_Géométrie_CORNICHE depuis profil - Position: Aucune; sets with these values: 2; IFC_Pset_Géométrie_CORNICHE Extérieure à partir d'un profil - Décalage: 0; Angle: 0 deg; Symétrie: no; Fermer: no; sets with these values: 2; IFC_Pset_Géométrie_BASE Extérieure à partir d'un profil - Angle: 0 deg; Symétrie: no; Côté: 0 cm; sets with these values: 2; IFC_Pset_Géométrie - Côté extérieur: 1; Invertir (dte/gche): no; Invertir (intérieur/extérieur): yes; Forme: Rectangle; Largeur: 127.902 cm; Hauteur: 269.968 cm; Hauteur 2: 0 cm; Rayon Arc: 0 cm; Rayon Cercle: 0 cm; Demi-axe horizontal: 0 cm; Demi-axe vertical: 0 cm; IFC_Pset_Géométrie_GRILLE - décalage: 0 cm; Offset latéral: 0 cm; Décalage supérieur: 0 cm; Décalage inférieur: 0 cm; Nombre accrochages latéraux: 0; Nombre d'accrochages supérieurs: 0; Nombre accrochages inférieurs: 0; IFC_Pset_Géométrie_Niche - Présent: no; Stratigraphie: default [130,00]; Épaisseur: 13 cm; Alignement: Intérieur; Décalage: 0 cm; IFC_Pset_Système de Référence Altimétrique_INFÉRIEUR - NIVEAU: Rez-de-chaussée (Rez-de-chaussée 1047); delta: 0.0128504 cm; sous Niveau: <aucun>; IFC_Pset_Données Métré - Surface de l'Ouverture: 34500 cm2; Surface de l'Ébrasement: 0 cm2; Surface du Seuil: 0 cm2; Surface du Seuil intérieur: 0 cm2; Volume du seuil: 0 cm3; Volume du seuil intérieur: 0 cm3; Surface de la Niche: 0 cm2; Surface de la Grille: 0 cm2; Volume de la Grille: 0 cm3
4294966347_11 | Rez-de-chaussée | -949 | 2002 | 2002 | 0 | -1292786862
4294966346_11 | Rez-de-chaussée | -950 | 2002 | 2002 | 0 | -1292786862
Baie 449532 | Niveau 1 | 449532 | 114 | 9006 | 1 | -746779066 | Description: _VTO_Baie; CTLG_EXTERNAL_LINK - 1, DocType: 9; 1, Tag: 211; 1, Crc: -732809594; IFC_Pset_Caractéristiques - ID: 449532; Numérotation: 132; Numéro niveau: 04; Titre niveau: Niveau 1; IFC_Pset_Géométrie_Allège - Hauteur: 0 cm; Stratigraphie: ...; Épaisseur: 0 cm; IFC_Pset_Géométrie_Ébrasement - Présent: no; Côté supérieur: no; Côté INFÉRIEUR: no; Épaisseur extérieure: 0 cm; Épaisseur latérale gauche: 0 cm; Épaisseur latérale droite: 0 cm; Épiasseur latérale supérieure: 0 cm; Épaisseur diagonale gauche: 0 cm; Épaisseur diagonale droite: 0 cm; Épaisseur diagonale inférieure: 0 cm; Épaisseur diagonale supérieure: 0 cm; Épaisseur intérieur: 0 cm; IFC_Pset_Géométrie_Seuil - Type: Aucun; Épaisseur: 0 cm; Épaisseur interne: 0 cm; Décalage séparation: 0 cm; Appui extérieur: 0 cm; Appui intérieur: 0 cm; Côté latéral externe: 0 cm; Côté latéral interne: 0 cm; IFC_Pset_Géométrie_Chambranle - Position: Aucun; Épaisseur Chambranle intérieur: 0 cm; Longueur Chambranle intérieur: 0 cm; Superposition Chambranle intérieur: 0 cm; Épaisseur Intrados: 0 cm; Épaisseur Chambranle extérieur: 0 cm; Largeur Chambranle extérieur: 0 cm; Superposition Chambranle extérieur: 0 cm; Épaisseur Intrados extérieur: 0 cm; Décalage séparation intrados: 0 cm; IFC_Pset_Géométrie_CORNICHE depuis profil - Position: Aucune; sets with these values: 2; IFC_Pset_Géométrie_CORNICHE Extérieure à partir d'un profil - Décalage: 0; Angle: 0 deg; Symétrie: no; Fermer: no; sets with these values: 2; IFC_Pset_Géométrie_BASE Extérieure à partir d'un profil - Angle: 0 deg; Symétrie: no; Côté: 0 cm; sets with these values: 2; IFC_Pset_Géométrie - Côté extérieur: 0; Invertir (dte/gche): no; Invertir (intérieur/extérieur): no; Forme: Arc + Rectangle; Largeur: 159.184 cm; Hauteur: 41.2107 cm; Hauteur 2: 0 cm; Rayon Arc: 19.5453 cm; Rayon Cercle: 0 cm; Demi-axe horizontal: 0 cm; Demi-axe vertical: 0 cm; IFC_Pset_Géométrie_GRILLE - décalage: 0 cm; Offset latéral: 0 cm; Décalage supérieur: 0 cm; Décalage inférieur: 0 cm; Nombre accrochages latéraux: 0; Nombre d'accrochages supérieurs: 0; Nombre accrochages inférieurs: 0; IFC_Pset_Géométrie_Niche - Présent: no; Stratigraphie: Paroi en béton armé [120,00]; Épaisseur: 12 cm; Alignement: Intérieur; Décalage: 0 cm; IFC_Pset_Système de Référence Altimétrique_INFÉRIEUR - NIVEAU: Niveau 1 (Niveau 1 2343); delta: 285 cm; sous Niveau: <aucun>; IFC_Pset_Données Métré - Surface de l'Ouverture: 8600 cm2; Surface de l'Ébrasement: 0 cm2; Surface du Seuil: 0 cm2; Surface du Seuil intérieur: 0 cm2; Volume du seuil: 0 cm3; Volume du seuil intérieur: 0 cm3; Surface de la Niche: 0 cm2; Surface de la Grille: 0 cm2; Volume de la Grille: 0 cm3
Baie 448691 | Niveau 1 | 448691 | 114 | 9006 | 1 | -746779066 | Description: _VTO_Baie; CTLG_EXTERNAL_LINK - 1, DocType: 9; 1, Tag: 211; 1, Crc: -732809594; IFC_Pset_Caractéristiques - ID: 448691; Numérotation: 116; Numéro niveau: 04; Titre niveau: Niveau 1; IFC_Pset_Géométrie_Allège - Hauteur: 0 cm; Stratigraphie: ...; Épaisseur: 0 cm; IFC_Pset_Géométrie_Ébrasement - Présent: no; Côté supérieur: no; Côté INFÉRIEUR: no; Épaisseur extérieure: 0 cm; Épaisseur latérale gauche: 0 cm; Épaisseur latérale droite: 0 cm; Épiasseur latérale supérieure: 0 cm; Épaisseur diagonale gauche: 0 cm; Épaisseur diagonale droite: 0 cm; Épaisseur diagonale inférieure: 0 cm; Épaisseur diagonale supérieure: 0 cm; Épaisseur intérieur: 0 cm; IFC_Pset_Géométrie_Seuil - Type: Aucun; Épaisseur: 0 cm; Épaisseur interne: 0 cm; Décalage séparation: 0 cm; Appui extérieur: 0 cm; Appui intérieur: 0 cm; Côté latéral externe: 0 cm; Côté latéral interne: 0 cm; IFC_Pset_Géométrie_Chambranle - Position: Aucun; Épaisseur Chambranle intérieur: 0 cm; Longueur Chambranle intérieur: 0 cm; Superposition Chambranle intérieur: 0 cm; Épaisseur Intrados: 0 cm; Épaisseur Chambranle extérieur: 0 cm; Largeur Chambranle extérieur: 0 cm; Superposition Chambranle extérieur: 0 cm; Épaisseur Intrados extérieur: 0 cm; Décalage séparation intrados: 0 cm; IFC_Pset_Géométrie_CORNICHE depuis profil - Position: Aucune; sets with these values: 2; IFC_Pset_Géométrie_CORNICHE Extérieure à partir d'un profil - Décalage: 0; Angle: 0 deg; Symétrie: no; Fermer: no; sets with these values: 2; IFC_Pset_Géométrie_BASE Extérieure à partir d'un profil - Angle: 0 deg; Symétrie: no; Côté: 0 cm; sets with these values: 2; IFC_Pset_Géométrie - Côté extérieur: 0; Invertir (dte/gche): no; Invertir (intérieur/extérieur): no; Forme: Arc + Rectangle; Largeur: 18.167 cm; Hauteur: 27.0965 cm; Hauteur 2: 0 cm; Rayon Arc: 9.08348 cm; Rayon Cercle: 0 cm; Demi-axe horizontal: 0 cm; Demi-axe vertical: 0 cm; IFC_Pset_Géométrie_GRILLE - décalage: 0 cm; Offset latéral: 0 cm; Décalage supérieur: 0 cm; Décalage inférieur: 0 cm; Nombre accrochages latéraux: 0; Nombre d'accrochages supérieurs: 0; Nombre accrochages inférieurs: 0; IFC_Pset_Géométrie_Niche - Présent: no; Stratigraphie: Paroi en béton armé [120,00]; Épaisseur: 12 cm; Alignement: Intérieur; Décalage: 0 cm; IFC_Pset_Système de Référence Altimétrique_INFÉRIEUR - NIVEAU: Niveau 1 (Niveau 1 2343); delta: 27.3907 cm; sous Niveau: <aucun>; IFC_Pset_Données Métré - Surface de l'Ouverture: 600 cm2; Surface de l'Ébrasement: 0 cm2; Surface du Seuil: 0 cm2; Surface du Seuil intérieur: 0 cm2; Volume du seuil: 0 cm3; Volume du seuil intérieur: 0 cm3; Surface de la Niche: 0 cm2; Surface de la Grille: 0 cm2; Volume de la Grille: 0 cm3
Baie 448690 | Niveau 1 | 448690 | 114 | 9006 | 1 | -746779066 | Description: _VTO_Baie; CTLG_EXTERNAL_LINK - 1, DocType: 9; 1, Tag: 211; 1, Crc: -732809594; IFC_Pset_Caractéristiques - ID: 448690; Numérotation: 115; Numéro niveau: 04; Titre niveau: Niveau 1; IFC_Pset_Géométrie_Allège - Hauteur: 0 cm; Stratigraphie: ...; Épaisseur: 0 cm; IFC_Pset_Géométrie_Ébrasement - Présent: no; Côté supérieur: no; Côté INFÉRIEUR: no; Épaisseur extérieure: 0 cm; Épaisseur latérale gauche: 0 cm; Épaisseur latérale droite: 0 cm; Épiasseur latérale supérieure: 0 cm; Épaisseur diagonale gauche: 0 cm; Épaisseur diagonale droite: 0 cm; Épaisseur diagonale inférieure: 0 cm; Épaisseur diagonale supérieure: 0 cm; Épaisseur intérieur: 0 cm; IFC_Pset_Géométrie_Seuil - Type: Aucun; Épaisseur: 0 cm; Épaisseur interne: 0 cm; Décalage séparation: 0 cm; Appui extérieur: 0 cm; Appui intérieur: 0 cm; Côté latéral externe: 0 cm; Côté latéral interne: 0 cm; IFC_Pset_Géométrie_Chambranle - Position: Aucun; Épaisseur Chambranle intérieur: 0 cm; Longueur Chambranle intérieur: 0 cm; Superposition Chambranle intérieur: 0 cm; Épaisseur Intrados: 0 cm; Épaisseur Chambranle extérieur: 0 cm; Largeur Chambranle extérieur: 0 cm; Superposition Chambranle extérieur: 0 cm; Épaisseur Intrados extérieur: 0 cm; Décalage séparation intrados: 0 cm; IFC_Pset_Géométrie_CORNICHE depuis profil - Position: Aucune; sets with these values: 2; IFC_Pset_Géométrie_CORNICHE Extérieure à partir d'un profil - Décalage: 0; Angle: 0 deg; Symétrie: no; Fermer: no; sets with these values: 2; IFC_Pset_Géométrie_BASE Extérieure à partir d'un profil - Angle: 0 deg; Symétrie: no; Côté: 0 cm; sets with these values: 2; IFC_Pset_Géométrie - Côté extérieur: 0; Invertir (dte/gche): no; Invertir (intérieur/extérieur): no; Forme: Arc + Rectangle; Largeur: 18.167 cm; Hauteur: 27.0965 cm; Hauteur 2: 0 cm; Rayon Arc: 9.08348 cm; Rayon Cercle: 0 cm; Demi-axe horizontal: 0 cm; Demi-axe vertical: 0 cm; IFC_Pset_Géométrie_GRILLE - décalage: 0 cm; Offset latéral: 0 cm; Décalage supérieur: 0 cm; Décalage inférieur: 0 cm; Nombre accrochages latéraux: 0; Nombre d'accrochages supérieurs: 0; Nombre accrochages inférieurs: 0; IFC_Pset_Géométrie_Niche - Présent: no; Stratigraphie: Paroi en béton armé [120,00]; Épaisseur: 12 cm; Alignement: Intérieur; Décalage: 0 cm; IFC_Pset_Système de Référence Altimétrique_INFÉRIEUR - NIVEAU: Niveau 1 (Niveau 1 2343); delta: 27.3907 cm; sous Niveau: <aucun>; IFC_Pset_Données Métré - Surface de l'Ouverture: 600 cm2; Surface de l'Ébrasement: 0 cm2; Surface du Seuil: 0 cm2; Surface du Seuil intérieur: 0 cm2; Volume du seuil: 0 cm3; Volume du seuil intérieur: 0 cm3; Surface de la Niche: 0 cm2; Surface de la Grille: 0 cm2; Volume de la Grille: 0 cm3
Baie 448686 | Niveau 1 | 448686 | 114 | 9006 | 1 | -746779066 | Description: _VTO_Baie; CTLG_EXTERNAL_LINK - 1, DocType: 9; 1, Tag: 211; 1, Crc: -732809594; IFC_Pset_Caractéristiques - ID: 448686; Numérotation: 112; Numéro niveau: 04; Titre niveau: Niveau 1; IFC_Pset_Géométrie_Allège - Hauteur: 0 cm; Stratigraphie: ...; Épaisseur: 0 cm; IFC_Pset_Géométrie_Ébrasement - Présent: no; Côté supérieur: no; Côté INFÉRIEUR: no; Épaisseur extérieure: 0 cm; Épaisseur latérale gauche: 0 cm; Épaisseur latérale droite: 0 cm; Épiasseur latérale supérieure: 0 cm; Épaisseur diagonale gauche: 0 cm; Épaisseur diagonale droite: 0 cm; Épaisseur diagonale inférieure: 0 cm; Épaisseur diagonale supérieure: 0 cm; Épaisseur intérieur: 0 cm; IFC_Pset_Géométrie_Seuil - Type: Aucun; Épaisseur: 0 cm; Épaisseur interne: 0 cm; Décalage séparation: 0 cm; Appui extérieur: 0 cm; Appui intérieur: 0 cm; Côté latéral externe: 0 cm; Côté latéral interne: 0 cm; IFC_Pset_Géométrie_Chambranle - Position: Aucun; Épaisseur Chambranle intérieur: 0 cm; Longueur Chambranle intérieur: 0 cm; Superposition Chambranle intérieur: 0 cm; Épaisseur Intrados: 0 cm; Épaisseur Chambranle extérieur: 0 cm; Largeur Chambranle extérieur: 0 cm; Superposition Chambranle extérieur: 0 cm; Épaisseur Intrados extérieur: 0 cm; Décalage séparation intrados: 0 cm; IFC_Pset_Géométrie_CORNICHE depuis profil - Position: Aucune; sets with these values: 2; IFC_Pset_Géométrie_CORNICHE Extérieure à partir d'un profil - Décalage: 0; Angle: 0 deg; Symétrie: no; Fermer: no; sets with these values: 2; IFC_Pset_Géométrie_BASE Extérieure à partir d'un profil - Angle: 0 deg; Symétrie: no; Côté: 0 cm; sets with these values: 2; IFC_Pset_Géométrie - Côté extérieur: 0; Invertir (dte/gche): no; Invertir (intérieur/extérieur): no; Forme: Arc + Rectangle; Largeur: 18.167 cm; Hauteur: 27.0965 cm; Hauteur 2: 0 cm; Rayon Arc: 9.08348 cm; Rayon Cercle: 0 cm; Demi-axe horizontal: 0 cm; Demi-axe vertical: 0 cm; IFC_Pset_Géométrie_GRILLE - décalage: 0 cm; Offset latéral: 0 cm; Décalage supérieur: 0 cm; Décalage inférieur: 0 cm; Nombre accrochages latéraux: 0; Nombre d'accrochages supérieurs: 0; Nombre accrochages inférieurs: 0; IFC_Pset_Géométrie_Niche - Présent: no; Stratigraphie: Paroi en béton armé [120,00]; Épaisseur: 12 cm; Alignement: Intérieur; Décalage: 0 cm; IFC_Pset_Système de Référence Altimétrique_INFÉRIEUR - NIVEAU: Niveau 1 (Niveau 1 2343); delta: 27.6724 cm; sous Niveau: <aucun>; IFC_Pset_Données Métré - Surface de l'Ouverture: 600 cm2; Surface de l'Ébrasement: 0 cm2; Surface du Seuil: 0 cm2; Surface du Seuil intérieur: 0 cm2; Volume du seuil: 0 cm3; Volume du seuil intérieur: 0 cm3; Surface de la Niche: 0 cm2; Surface de la Grille: 0 cm2; Volume de la Grille: 0 cm3
Baie 448689 | Niveau 1 | 448689 | 114 | 9006 | 1 | -746779066 | Description: _VTO_Baie; CTLG_EXTERNAL_LINK - 1, DocType: 9; 1, Tag: 211; 1, Crc: -732809594; IFC_Pset_Caractéristiques - ID: 448689; Numérotation: 114; Numéro niveau: 04; Titre niveau: Niveau 1; IFC_Pset_Géométrie_Allège - Hauteur: 0 cm; Stratigraphie: ...; Épaisseur: 0 cm; IFC_Pset_Géométrie_Ébrasement - Présent: no; Côté supérieur: no; Côté INFÉRIEUR: no; Épaisseur extérieure: 0 cm; Épaisseur latérale gauche: 0 cm; Épaisseur latérale droite: 0 cm; Épiasseur latérale supérieure: 0 cm; Épaisseur diagonale gauche: 0 cm; Épaisseur diagonale droite: 0 cm; Épaisseur diagonale inférieure: 0 cm; Épaisseur diagonale supérieure: 0 cm; Épaisseur intérieur: 0 cm; IFC_Pset_Géométrie_Seuil - Type: Aucun; Épaisseur: 0 cm; Épaisseur interne: 0 cm; Décalage séparation: 0 cm; Appui extérieur: 0 cm; Appui intérieur: 0 cm; Côté latéral externe: 0 cm; Côté latéral interne: 0 cm; IFC_Pset_Géométrie_Chambranle - Position: Aucun; Épaisseur Chambranle intérieur: 0 cm; Longueur Chambranle intérieur: 0 cm; Superposition Chambranle intérieur: 0 cm; Épaisseur Intrados: 0 cm; Épaisseur Chambranle extérieur: 0 cm; Largeur Chambranle extérieur: 0 cm; Superposition Chambranle extérieur: 0 cm; Épaisseur Intrados extérieur: 0 cm; Décalage séparation intrados: 0 cm; IFC_Pset_Géométrie_CORNICHE depuis profil - Position: Aucune; sets with these values: 2; IFC_Pset_Géométrie_CORNICHE Extérieure à partir d'un profil - Décalage: 0; Angle: 0 deg; Symétrie: no; Fermer: no; sets with these values: 2; IFC_Pset_Géométrie_BASE Extérieure à partir d'un profil - Angle: 0 deg; Symétrie: no; Côté: 0 cm; sets with these values: 2; IFC_Pset_Géométrie - Côté extérieur: 0; Invertir (dte/gche): no; Invertir (intérieur/extérieur): no; Forme: Arc + Rectangle; Largeur: 18.167 cm; Hauteur: 27.0965 cm; Hauteur 2: 0 cm; Rayon Arc: 9.08348 cm; Rayon Cercle: 0 cm; Demi-axe horizontal: 0 cm; Demi-axe vertical: 0 cm; IFC_Pset_Géométrie_GRILLE - décalage: 0 cm; Offset latéral: 0 cm; Décalage supérieur: 0 cm; Décalage inférieur: 0 cm; Nombre accrochages latéraux: 0; Nombre d'accrochages supérieurs: 0; Nombre accrochages inférieurs: 0; IFC_Pset_Géométrie_Niche - Présent: no; Stratigraphie: Paroi en béton armé [120,00]; Épaisseur: 12 cm; Alignement: Intérieur; Décalage: 0 cm; IFC_Pset_Système de Référence Altimétrique_INFÉRIEUR - NIVEAU: Niveau 1 (Niveau 1 2343); delta: 27.6724 cm; sous Niveau: <aucun>; IFC_Pset_Données Métré - Surface de l'Ouverture: 600 cm2; Surface de l'Ébrasement: 0 cm2; Surface du Seuil: 0 cm2; Surface du Seuil intérieur: 0 cm2; Volume du seuil: 0 cm3; Volume du seuil intérieur: 0 cm3; Surface de la Niche: 0 cm2; Surface de la Grille: 0 cm2; Volume de la Grille: 0 cm3
Baie 448688 | Niveau 1 | 448688 | 114 | 9006 | 1 | -746779066 | Description: _VTO_Baie; CTLG_EXTERNAL_LINK - 1, DocType: 9; 1, Tag: 211; 1, Crc: -732809594; IFC_Pset_Caractéristiques - ID: 448688; Numérotation: 113; Numéro niveau: 04; Titre niveau: Niveau 1; IFC_Pset_Géométrie_Allège - Hauteur: 0 cm; Stratigraphie: ...; Épaisseur: 0 cm; IFC_Pset_Géométrie_Ébrasement - Présent: no; Côté supérieur: no; Côté INFÉRIEUR: no; Épaisseur extérieure: 0 cm; Épaisseur latérale gauche: 0 cm; Épaisseur latérale droite: 0 cm; Épiasseur latérale supérieure: 0 cm; Épaisseur diagonale gauche: 0 cm; Épaisseur diagonale droite: 0 cm; Épaisseur diagonale inférieure: 0 cm; Épaisseur diagonale supérieure: 0 cm; Épaisseur intérieur: 0 cm; IFC_Pset_Géométrie_Seuil - Type: Aucun; Épaisseur: 0 cm; Épaisseur interne: 0 cm; Décalage séparation: 0 cm; Appui extérieur: 0 cm; Appui intérieur: 0 cm; Côté latéral externe: 0 cm; Côté latéral interne: 0 cm; IFC_Pset_Géométrie_Chambranle - Position: Aucun; Épaisseur Chambranle intérieur: 0 cm; Longueur Chambranle intérieur: 0 cm; Superposition Chambranle intérieur: 0 cm; Épaisseur Intrados: 0 cm; Épaisseur Chambranle extérieur: 0 cm; Largeur Chambranle extérieur: 0 cm; Superposition Chambranle extérieur: 0 cm; Épaisseur Intrados extérieur: 0 cm; Décalage séparation intrados: 0 cm; IFC_Pset_Géométrie_CORNICHE depuis profil - Position: Aucune; sets with these values: 2; IFC_Pset_Géométrie_CORNICHE Extérieure à partir d'un profil - Décalage: 0; Angle: 0 deg; Symétrie: no; Fermer: no; sets with these values: 2; IFC_Pset_Géométrie_BASE Extérieure à partir d'un profil - Angle: 0 deg; Symétrie: no; Côté: 0 cm; sets with these values: 2; IFC_Pset_Géométrie - Côté extérieur: 0; Invertir (dte/gche): no; Invertir (intérieur/extérieur): no; Forme: Arc + Rectangle; Largeur: 18.167 cm; Hauteur: 27.0965 cm; Hauteur 2: 0 cm; Rayon Arc: 9.08348 cm; Rayon Cercle: 0 cm; Demi-axe horizontal: 0 cm; Demi-axe vertical: 0 cm; IFC_Pset_Géométrie_GRILLE - décalage: 0 cm; Offset latéral: 0 cm; Décalage supérieur: 0 cm; Décalage inférieur: 0 cm; Nombre accrochages latéraux: 0; Nombre d'accrochages supérieurs: 0; Nombre accrochages inférieurs: 0; IFC_Pset_Géométrie_Niche - Présent: no; Stratigraphie: Paroi en béton armé [120,00]; Épaisseur: 12 cm; Alignement: Intérieur; Décalage: 0 cm; IFC_Pset_Système de Référence Altimétrique_INFÉRIEUR - NIVEAU: Niveau 1 (Niveau 1 2343); delta: 27.6724 cm; sous Niveau: <aucun>; IFC_Pset_Données Métré - Surface de l'Ouverture: 600 cm2; Surface de l'Ébrasement: 0 cm2; Surface du Seuil: 0 cm2; Surface du Seuil intérieur: 0 cm2; Volume du seuil: 0 cm3; Volume du seuil intérieur: 0 cm3; Surface de la Niche: 0 cm2; Surface de la Grille: 0 cm2; Volume de la Grille: 0 cm3
Baie 449483 | Niveau 1 | 449483 | 114 | 9006 | 1 | -746779066 | Description: _VTO_Baie; CTLG_EXTERNAL_LINK - 1, DocType: 9; 1, Tag: 211; 1, Crc: -732809594; IFC_Pset_Caractéristiques - ID: 449483; Numérotation: 127; Numéro niveau: 04; Titre niveau: Niveau 1; IFC_Pset_Géométrie_Allège - Hauteur: 0 cm; Stratigraphie: ...; Épaisseur: 0 cm; IFC_Pset_Géométrie_Ébrasement - Présent: no; Côté supérieur: no; Côté INFÉRIEUR: no; Épaisseur extérieure: 0 cm; Épaisseur latérale gauche: 0 cm; Épaisseur latérale droite: 0 cm; Épiasseur latérale supérieure: 0 cm; Épaisseur diagonale gauche: 0 cm; Épaisseur diagonale droite: 0 cm; Épaisseur diagonale inférieure: 0 cm; Épaisseur diagonale supérieure: 0 cm; Épaisseur intérieur: 0 cm; IFC_Pset_Géométrie_Seuil - Type: Aucun; Épaisseur: 0 cm; Épaisseur interne: 0 cm; Décalage séparation: 0 cm; Appui extérieur: 0 cm; Appui intérieur: 0 cm; Côté latéral externe: 0 cm; Côté latéral interne: 0 cm; IFC_Pset_Géométrie_Chambranle - Position: Aucun; Épaisseur Chambranle intérieur: 0 cm; Longueur Chambranle intérieur: 0 cm; Superposition Chambranle intérieur: 0 cm; Épaisseur Intrados: 0 cm; Épaisseur Chambranle extérieur: 0 cm; Largeur Chambranle extérieur: 0 cm; Superposition Chambranle extérieur: 0 cm; Épaisseur Intrados extérieur: 0 cm; Décalage séparation intrados: 0 cm; IFC_Pset_Géométrie_CORNICHE depuis profil - Position: Aucune; sets with these values: 2; IFC_Pset_Géométrie_CORNICHE Extérieure à partir d'un profil - Décalage: 0; Angle: 0 deg; Symétrie: no; Fermer: no; sets with these values: 2; IFC_Pset_Géométrie_BASE Extérieure à partir d'un profil - Angle: 0 deg; Symétrie: no; Côté: 0 cm; sets with these values: 2; IFC_Pset_Géométrie - Côté extérieur: 0; Invertir (dte/gche): no; Invertir (intérieur/extérieur): no; Forme: Arc + Rectangle; Largeur: 18.167 cm; Hauteur: 27.0965 cm; Hauteur 2: 0 cm; Rayon Arc: 9.08348 cm; Rayon Cercle: 0 cm; Demi-axe horizontal: 0 cm; Demi-axe vertical: 0 cm; IFC_Pset_Géométrie_GRILLE - décalage: 0 cm; Offset latéral: 0 cm; Décalage supérieur: 0 cm; Décalage inférieur: 0 cm; Nombre accrochages latéraux: 0; Nombre d'accrochages supérieurs: 0; Nombre accrochages inférieurs: 0; IFC_Pset_Géométrie_Niche - Présent: no; Stratigraphie: Paroi en béton armé [120,00]; Épaisseur: 12 cm; Alignement: Intérieur; Décalage: 0 cm; IFC_Pset_Système de Référence Altimétrique_INFÉRIEUR - NIVEAU: Niveau 1 (Niveau 1 2343); delta: 27.6724 cm; sous Niveau: <aucun>; IFC_Pset_Données Métré - Surface de l'Ouverture: 600 cm2; Surface de l'Ébrasement: 0 cm2; Surface du Seuil: 0 cm2; Surface du Seuil intérieur: 0 cm2; Volume du seuil: 0 cm3; Volume du seuil intérieur: 0 cm3; Surface de la Niche: 0 cm2; Surface de la Grille: 0 cm2; Volume de la Grille: 0 cm3
Baie 449484 | Niveau 1 | 449484 | 114 | 9006 | 1 | -746779066 | Description: _VTO_Baie; CTLG_EXTERNAL_LINK - 1, DocType: 9; 1, Tag: 211; 1, Crc: -732809594; IFC_Pset_Caractéristiques - ID: 449484; Numérotation: 128; Numéro niveau: 04; Titre niveau: Niveau 1; IFC_Pset_Géométrie_Allège - Hauteur: 0 cm; Stratigraphie: ...; Épaisseur: 0 cm; IFC_Pset_Géométrie_Ébrasement - Présent: no; Côté supérieur: no; Côté INFÉRIEUR: no; Épaisseur extérieure: 0 cm; Épaisseur latérale gauche: 0 cm; Épaisseur latérale droite: 0 cm; Épiasseur latérale supérieure: 0 cm; Épaisseur diagonale gauche: 0 cm; Épaisseur diagonale droite: 0 cm; Épaisseur diagonale inférieure: 0 cm; Épaisseur diagonale supérieure: 0 cm; Épaisseur intérieur: 0 cm; IFC_Pset_Géométrie_Seuil - Type: Aucun; Épaisseur: 0 cm; Épaisseur interne: 0 cm; Décalage séparation: 0 cm; Appui extérieur: 0 cm; Appui intérieur: 0 cm; Côté latéral externe: 0 cm; Côté latéral interne: 0 cm; IFC_Pset_Géométrie_Chambranle - Position: Aucun; Épaisseur Chambranle intérieur: 0 cm; Longueur Chambranle intérieur: 0 cm; Superposition Chambranle intérieur: 0 cm; Épaisseur Intrados: 0 cm; Épaisseur Chambranle extérieur: 0 cm; Largeur Chambranle extérieur: 0 cm; Superposition Chambranle extérieur: 0 cm; Épaisseur Intrados extérieur: 0 cm; Décalage séparation intrados: 0 cm; IFC_Pset_Géométrie_CORNICHE depuis profil - Position: Aucune; sets with these values: 2; IFC_Pset_Géométrie_CORNICHE Extérieure à partir d'un profil - Décalage: 0; Angle: 0 deg; Symétrie: no; Fermer: no; sets with these values: 2; IFC_Pset_Géométrie_BASE Extérieure à partir d'un profil - Angle: 0 deg; Symétrie: no; Côté: 0 cm; sets with these values: 2; IFC_Pset_Géométrie - Côté extérieur: 0; Invertir (dte/gche): no; Invertir (intérieur/extérieur): no; Forme: Arc + Rectangle; Largeur: 18.167 cm; Hauteur: 27.0965 cm; Hauteur 2: 0 cm; Rayon Arc: 9.08348 cm; Rayon Cercle: 0 cm; Demi-axe horizontal: 0 cm; Demi-axe vertical: 0 cm; IFC_Pset_Géométrie_GRILLE - décalage: 0 cm; Offset latéral: 0 cm; Décalage supérieur: 0 cm; Décalage inférieur: 0 cm; Nombre accrochages latéraux: 0; Nombre d'accrochages supérieurs: 0; Nombre accrochages inférieurs: 0; IFC_Pset_Géométrie_Niche - Présent: no; Stratigraphie: Paroi en béton armé [120,00]; Épaisseur: 12 cm; Alignement: Intérieur; Décalage: 0 cm; IFC_Pset_Système de Référence Altimétrique_INFÉRIEUR - NIVEAU: Niveau 1 (Niveau 1 2343); delta: 27.6724 cm; sous Niveau: <aucun>; IFC_Pset_Données Métré - Surface de l'Ouverture: 600 cm2; Surface de l'Ébrasement: 0 cm2; Surface du Seuil: 0 cm2; Surface du Seuil intérieur: 0 cm2; Volume du seuil: 0 cm3; Volume du seuil intérieur: 0 cm3; Surface de la Niche: 0 cm2; Surface de la Grille: 0 cm2; Volume de la Grille: 0 cm3
Baie 449486 | Niveau 1 | 449486 | 114 | 9006 | 1 | -746779066 | Description: _VTO_Baie; CTLG_EXTERNAL_LINK - 1, DocType: 9; 1, Tag: 211; 1, Crc: -732809594; IFC_Pset_Caractéristiques - ID: 449486; Numérotation: 130; Numéro niveau: 04; Titre niveau: Niveau 1; IFC_Pset_Géométrie_Allège - Hauteur: 0 cm; Stratigraphie: ...; Épaisseur: 0 cm; IFC_Pset_Géométrie_Ébrasement - Présent: no; Côté supérieur: no; Côté INFÉRIEUR: no; Épaisseur extérieure: 0 cm; Épaisseur latérale gauche: 0 cm; Épaisseur latérale droite: 0 cm; Épiasseur latérale supérieure: 0 cm; Épaisseur diagonale gauche: 0 cm; Épaisseur diagonale droite: 0 cm; Épaisseur diagonale inférieure: 0 cm; Épaisseur diagonale supérieure: 0 cm; Épaisseur intérieur: 0 cm; IFC_Pset_Géométrie_Seuil - Type: Aucun; Épaisseur: 0 cm; Épaisseur interne: 0 cm; Décalage séparation: 0 cm; Appui extérieur: 0 cm; Appui intérieur: 0 cm; Côté latéral externe: 0 cm; Côté latéral interne: 0 cm; IFC_Pset_Géométrie_Chambranle - Position: Aucun; Épaisseur Chambranle intérieur: 0 cm; Longueur Chambranle intérieur: 0 cm; Superposition Chambranle intérieur: 0 cm; Épaisseur Intrados: 0 cm; Épaisseur Chambranle extérieur: 0 cm; Largeur Chambranle extérieur: 0 cm; Superposition Chambranle extérieur: 0 cm; Épaisseur Intrados extérieur: 0 cm; Décalage séparation intrados: 0 cm; IFC_Pset_Géométrie_CORNICHE depuis profil - Position: Aucune; sets with these values: 2; IFC_Pset_Géométrie_CORNICHE Extérieure à partir d'un profil - Décalage: 0; Angle: 0 deg; Symétrie: no; Fermer: no; sets with these values: 2; IFC_Pset_Géométrie_BASE Extérieure à partir d'un profil - Angle: 0 deg; Symétrie: no; Côté: 0 cm; sets with these values: 2; IFC_Pset_Géométrie - Côté extérieur: 0; Invertir (dte/gche): no; Invertir (intérieur/extérieur): no; Forme: Arc + Rectangle; Largeur: 18.167 cm; Hauteur: 27.0965 cm; Hauteur 2: 0 cm; Rayon Arc: 9.08348 cm; Rayon Cercle: 0 cm; Demi-axe horizontal: 0 cm; Demi-axe vertical: 0 cm; IFC_Pset_Géométrie_GRILLE - décalage: 0 cm; Offset latéral: 0 cm; Décalage supérieur: 0 cm; Décalage inférieur: 0 cm; Nombre accrochages latéraux: 0; Nombre d'accrochages supérieurs: 0; Nombre accrochages inférieurs: 0; IFC_Pset_Géométrie_Niche - Présent: no; Stratigraphie: Paroi en béton armé [120,00]; Épaisseur: 12 cm; Alignement: Intérieur; Décalage: 0 cm; IFC_Pset_Système de Référence Altimétrique_INFÉRIEUR - NIVEAU: Niveau 1 (Niveau 1 2343); delta: 27.3907 cm; sous Niveau: <aucun>; IFC_Pset_Données Métré - Surface de l'Ouverture: 600 cm2; Surface de l'Ébrasement: 0 cm2; Surface du Seuil: 0 cm2; Surface du Seuil intérieur: 0 cm2; Volume du seuil: 0 cm3; Volume du seuil intérieur: 0 cm3; Surface de la Niche: 0 cm2; Surface de la Grille: 0 cm2; Volume de la Grille: 0 cm3
Baie 449485 | Niveau 1 | 449485 | 114 | 9006 | 1 | -746779066 | Description: _VTO_Baie; CTLG_EXTERNAL_LINK - 1, DocType: 9; 1, Tag: 211; 1, Crc: -732809594; IFC_Pset_Caractéristiques - ID: 449485; Numérotation: 129; Numéro niveau: 04; Titre niveau: Niveau 1; IFC_Pset_Géométrie_Allège - Hauteur: 0 cm; Stratigraphie: ...; Épaisseur: 0 cm; IFC_Pset_Géométrie_Ébrasement - Présent: no; Côté supérieur: no; Côté INFÉRIEUR: no; Épaisseur extérieure: 0 cm; Épaisseur latérale gauche: 0 cm; Épaisseur latérale droite: 0 cm; Épiasseur latérale supérieure: 0 cm; Épaisseur diagonale gauche: 0 cm; Épaisseur diagonale droite: 0 cm; Épaisseur diagonale inférieure: 0 cm; Épaisseur diagonale supérieure: 0 cm; Épaisseur intérieur: 0 cm; IFC_Pset_Géométrie_Seuil - Type: Aucun; Épaisseur: 0 cm; Épaisseur interne: 0 cm; Décalage séparation: 0 cm; Appui extérieur: 0 cm; Appui intérieur: 0 cm; Côté latéral externe: 0 cm; Côté latéral interne: 0 cm; IFC_Pset_Géométrie_Chambranle - Position: Aucun; Épaisseur Chambranle intérieur: 0 cm; Longueur Chambranle intérieur: 0 cm; Superposition Chambranle intérieur: 0 cm; Épaisseur Intrados: 0 cm; Épaisseur Chambranle extérieur: 0 cm; Largeur Chambranle extérieur: 0 cm; Superposition Chambranle extérieur: 0 cm; Épaisseur Intrados extérieur: 0 cm; Décalage séparation intrados: 0 cm; IFC_Pset_Géométrie_CORNICHE depuis profil - Position: Aucune; sets with these values: 2; IFC_Pset_Géométrie_CORNICHE Extérieure à partir d'un profil - Décalage: 0; Angle: 0 deg; Symétrie: no; Fermer: no; sets with these values: 2; IFC_Pset_Géométrie_BASE Extérieure à partir d'un profil - Angle: 0 deg; Symétrie: no; Côté: 0 cm; sets with these values: 2; IFC_Pset_Géométrie - Côté extérieur: 0; Invertir (dte/gche): no; Invertir (intérieur/extérieur): no; Forme: Arc + Rectangle; Largeur: 18.167 cm; Hauteur: 27.0965 cm; Hauteur 2: 0 cm; Rayon Arc: 9.08348 cm; Rayon Cercle: 0 cm; Demi-axe horizontal: 0 cm; Demi-axe vertical: 0 cm; IFC_Pset_Géométrie_GRILLE - décalage: 0 cm; Offset latéral: 0 cm; Décalage supérieur: 0 cm; Décalage inférieur: 0 cm; Nombre accrochages latéraux: 0; Nombre d'accrochages supérieurs: 0; Nombre accrochages inférieurs: 0; IFC_Pset_Géométrie_Niche - Présent: no; Stratigraphie: Paroi en béton armé [120,00]; Épaisseur: 12 cm; Alignement: Intérieur; Décalage: 0 cm; IFC_Pset_Système de Référence Altimétrique_INFÉRIEUR - NIVEAU: Niveau 1 (Niveau 1 2343); delta: 27.6724 cm; sous Niveau: <aucun>; IFC_Pset_Données Métré - Surface de l'Ouverture: 600 cm2; Surface de l'Ébrasement: 0 cm2; Surface du Seuil: 0 cm2; Surface du Seuil intérieur: 0 cm2; Volume du seuil: 0 cm3; Volume du seuil intérieur: 0 cm3; Surface de la Niche: 0 cm2; Surface de la Grille: 0 cm2; Volume de la Grille: 0 cm3
Baie 449487 | Niveau 1 | 449487 | 114 | 9006 | 1 | -746779066 | Description: _VTO_Baie; CTLG_EXTERNAL_LINK - 1, DocType: 9; 1, Tag: 211; 1, Crc: -732809594; IFC_Pset_Caractéristiques - ID: 449487; Numérotation: 131; Numéro niveau: 04; Titre niveau: Niveau 1; IFC_Pset_Géométrie_Allège - Hauteur: 0 cm; Stratigraphie: ...; Épaisseur: 0 cm; IFC_Pset_Géométrie_Ébrasement - Présent: no; Côté supérieur: no; Côté INFÉRIEUR: no; Épaisseur extérieure: 0 cm; Épaisseur latérale gauche: 0 cm; Épaisseur latérale droite: 0 cm; Épiasseur latérale supérieure: 0 cm; Épaisseur diagonale gauche: 0 cm; Épaisseur diagonale droite: 0 cm; Épaisseur diagonale inférieure: 0 cm; Épaisseur diagonale supérieure: 0 cm; Épaisseur intérieur: 0 cm; IFC_Pset_Géométrie_Seuil - Type: Aucun; Épaisseur: 0 cm; Épaisseur interne: 0 cm; Décalage séparation: 0 cm; Appui extérieur: 0 cm; Appui intérieur: 0 cm; Côté latéral externe: 0 cm; Côté latéral interne: 0 cm; IFC_Pset_Géométrie_Chambranle - Position: Aucun; Épaisseur Chambranle intérieur: 0 cm; Longueur Chambranle intérieur: 0 cm; Superposition Chambranle intérieur: 0 cm; Épaisseur Intrados: 0 cm; Épaisseur Chambranle extérieur: 0 cm; Largeur Chambranle extérieur: 0 cm; Superposition Chambranle extérieur: 0 cm; Épaisseur Intrados extérieur: 0 cm; Décalage séparation intrados: 0 cm; IFC_Pset_Géométrie_CORNICHE depuis profil - Position: Aucune; sets with these values: 2; IFC_Pset_Géométrie_CORNICHE Extérieure à partir d'un profil - Décalage: 0; Angle: 0 deg; Symétrie: no; Fermer: no; sets with these values: 2; IFC_Pset_Géométrie_BASE Extérieure à partir d'un profil - Angle: 0 deg; Symétrie: no; Côté: 0 cm; sets with these values: 2; IFC_Pset_Géométrie - Côté extérieur: 0; Invertir (dte/gche): no; Invertir (intérieur/extérieur): no; Forme: Arc + Rectangle; Largeur: 18.167 cm; Hauteur: 27.0965 cm; Hauteur 2: 0 cm; Rayon Arc: 9.08348 cm; Rayon Cercle: 0 cm; Demi-axe horizontal: 0 cm; Demi-axe vertical: 0 cm; IFC_Pset_Géométrie_GRILLE - décalage: 0 cm; Offset latéral: 0 cm; Décalage supérieur: 0 cm; Décalage inférieur: 0 cm; Nombre accrochages latéraux: 0; Nombre d'accrochages supérieurs: 0; Nombre accrochages inférieurs: 0; IFC_Pset_Géométrie_Niche - Présent: no; Stratigraphie: Paroi en béton armé [120,00]; Épaisseur: 12 cm; Alignement: Intérieur; Décalage: 0 cm; IFC_Pset_Système de Référence Altimétrique_INFÉRIEUR - NIVEAU: Niveau 1 (Niveau 1 2343); delta: 27.3907 cm; sous Niveau: <aucun>; IFC_Pset_Données Métré - Surface de l'Ouverture: 600 cm2; Surface de l'Ébrasement: 0 cm2; Surface du Seuil: 0 cm2; Surface du Seuil intérieur: 0 cm2; Volume du seuil: 0 cm3; Volume du seuil intérieur: 0 cm3; Surface de la Niche: 0 cm2; Surface de la Grille: 0 cm2; Volume de la Grille: 0 cm3
Baie 449445 | Niveau 1 | 449445 | 114 | 9006 | 1 | -746779066 | Description: _VTO_Baie; CTLG_EXTERNAL_LINK - 1, DocType: 9; 1, Tag: 211; 1, Crc: -732809594; IFC_Pset_Caractéristiques - ID: 449445; Numérotation: 117; Numéro niveau: 04; Titre niveau: Niveau 1; IFC_Pset_Géométrie_Allège - Hauteur: 0 cm; Stratigraphie: ...; Épaisseur: 0 cm; IFC_Pset_Géométrie_Ébrasement - Présent: no; Côté supérieur: no; Côté INFÉRIEUR: no; Épaisseur extérieure: 0 cm; Épaisseur latérale gauche: 0 cm; Épaisseur latérale droite: 0 cm; Épiasseur latérale supérieure: 0 cm; Épaisseur diagonale gauche: 0 cm; Épaisseur diagonale droite: 0 cm; Épaisseur diagonale inférieure: 0 cm; Épaisseur diagonale supérieure: 0 cm; Épaisseur intérieur: 0 cm; IFC_Pset_Géométrie_Seuil - Type: Aucun; Épaisseur: 0 cm; Épaisseur interne: 0 cm; Décalage séparation: 0 cm; Appui extérieur: 0 cm; Appui intérieur: 0 cm; Côté latéral externe: 0 cm; Côté latéral interne: 0 cm; IFC_Pset_Géométrie_Chambranle - Position: Aucun; Épaisseur Chambranle intérieur: 0 cm; Longueur Chambranle intérieur: 0 cm; Superposition Chambranle intérieur: 0 cm; Épaisseur Intrados: 0 cm; Épaisseur Chambranle extérieur: 0 cm; Largeur Chambranle extérieur: 0 cm; Superposition Chambranle extérieur: 0 cm; Épaisseur Intrados extérieur: 0 cm; Décalage séparation intrados: 0 cm; IFC_Pset_Géométrie_CORNICHE depuis profil - Position: Aucune; sets with these values: 2; IFC_Pset_Géométrie_CORNICHE Extérieure à partir d'un profil - Décalage: 0; Angle: 0 deg; Symétrie: no; Fermer: no; sets with these values: 2; IFC_Pset_Géométrie_BASE Extérieure à partir d'un profil - Angle: 0 deg; Symétrie: no; Côté: 0 cm; sets with these values: 2; IFC_Pset_Géométrie - Côté extérieur: 0; Invertir (dte/gche): no; Invertir (intérieur/extérieur): no; Forme: Arc + Rectangle; Largeur: 18.167 cm; Hauteur: 27.0965 cm; Hauteur 2: 0 cm; Rayon Arc: 9.08348 cm; Rayon Cercle: 0 cm; Demi-axe horizontal: 0 cm; Demi-axe vertical: 0 cm; IFC_Pset_Géométrie_GRILLE - décalage: 0 cm; Offset latéral: 0 cm; Décalage supérieur: 0 cm; Décalage inférieur: 0 cm; Nombre accrochages latéraux: 0; Nombre d'accrochages supérieurs: 0; Nombre accrochages inférieurs: 0; IFC_Pset_Géométrie_Niche - Présent: no; Stratigraphie: Paroi en béton armé [120,00]; Épaisseur: 12 cm; Alignement: Intérieur; Décalage: 0 cm; IFC_Pset_Système de Référence Altimétrique_INFÉRIEUR - NIVEAU: Niveau 1 (Niveau 1 2343); delta: 27.6724 cm; sous Niveau: <aucun>; IFC_Pset_Données Métré - Surface de l'Ouverture: 600 cm2; Surface de l'Ébrasement: 0 cm2; Surface du Seuil: 0 cm2; Surface du Seuil intérieur: 0 cm2; Volume du seuil: 0 cm3; Volume du seuil intérieur: 0 cm3; Surface de la Niche: 0 cm2; Surface de la Grille: 0 cm2; Volume de la Grille: 0 cm3
Baie 449447 | Niveau 1 | 449447 | 114 | 9006 | 1 | -746779066 | Description: _VTO_Baie; CTLG_EXTERNAL_LINK - 1, DocType: 9; 1, Tag: 211; 1, Crc: -732809594; IFC_Pset_Caractéristiques - ID: 449447; Numérotation: 119; Numéro niveau: 04; Titre niveau: Niveau 1; IFC_Pset_Géométrie_Allège - Hauteur: 0 cm; Stratigraphie: ...; Épaisseur: 0 cm; IFC_Pset_Géométrie_Ébrasement - Présent: no; Côté supérieur: no; Côté INFÉRIEUR: no; Épaisseur extérieure: 0 cm; Épaisseur latérale gauche: 0 cm; Épaisseur latérale droite: 0 cm; Épiasseur latérale supérieure: 0 cm; Épaisseur diagonale gauche: 0 cm; Épaisseur diagonale droite: 0 cm; Épaisseur diagonale inférieure: 0 cm; Épaisseur diagonale supérieure: 0 cm; Épaisseur intérieur: 0 cm; IFC_Pset_Géométrie_Seuil - Type: Aucun; Épaisseur: 0 cm; Épaisseur interne: 0 cm; Décalage séparation: 0 cm; Appui extérieur: 0 cm; Appui intérieur: 0 cm; Côté latéral externe: 0 cm; Côté latéral interne: 0 cm; IFC_Pset_Géométrie_Chambranle - Position: Aucun; Épaisseur Chambranle intérieur: 0 cm; Longueur Chambranle intérieur: 0 cm; Superposition Chambranle intérieur: 0 cm; Épaisseur Intrados: 0 cm; Épaisseur Chambranle extérieur: 0 cm; Largeur Chambranle extérieur: 0 cm; Superposition Chambranle extérieur: 0 cm; Épaisseur Intrados extérieur: 0 cm; Décalage séparation intrados: 0 cm; IFC_Pset_Géométrie_CORNICHE depuis profil - Position: Aucune; sets with these values: 2; IFC_Pset_Géométrie_CORNICHE Extérieure à partir d'un profil - Décalage: 0; Angle: 0 deg; Symétrie: no; Fermer: no; sets with these values: 2; IFC_Pset_Géométrie_BASE Extérieure à partir d'un profil - Angle: 0 deg; Symétrie: no; Côté: 0 cm; sets with these values: 2; IFC_Pset_Géométrie - Côté extérieur: 0; Invertir (dte/gche): no; Invertir (intérieur/extérieur): no; Forme: Arc + Rectangle; Largeur: 18.167 cm; Hauteur: 27.0965 cm; Hauteur 2: 0 cm; Rayon Arc: 9.08348 cm; Rayon Cercle: 0 cm; Demi-axe horizontal: 0 cm; Demi-axe vertical: 0 cm; IFC_Pset_Géométrie_GRILLE - décalage: 0 cm; Offset latéral: 0 cm; Décalage supérieur: 0 cm; Décalage inférieur: 0 cm; Nombre accrochages latéraux: 0; Nombre d'accrochages supérieurs: 0; Nombre accrochages inférieurs: 0; IFC_Pset_Géométrie_Niche - Présent: no; Stratigraphie: Paroi en béton armé [120,00]; Épaisseur: 12 cm; Alignement: Intérieur; Décalage: 0 cm; IFC_Pset_Système de Référence Altimétrique_INFÉRIEUR - NIVEAU: Niveau 1 (Niveau 1 2343); delta: 27.6724 cm; sous Niveau: <aucun>; IFC_Pset_Données Métré - Surface de l'Ouverture: 600 cm2; Surface de l'Ébrasement: 0 cm2; Surface du Seuil: 0 cm2; Surface du Seuil intérieur: 0 cm2; Volume du seuil: 0 cm3; Volume du seuil intérieur: 0 cm3; Surface de la Niche: 0 cm2; Surface de la Grille: 0 cm2; Volume de la Grille: 0 cm3
Baie 449446 | Niveau 1 | 449446 | 114 | 9006 | 1 | -746779066 | Description: _VTO_Baie; CTLG_EXTERNAL_LINK - 1, DocType: 9; 1, Tag: 211; 1, Crc: -732809594; IFC_Pset_Caractéristiques - ID: 449446; Numérotation: 118; Numéro niveau: 04; Titre niveau: Niveau 1; IFC_Pset_Géométrie_Allège - Hauteur: 0 cm; Stratigraphie: ...; Épaisseur: 0 cm; IFC_Pset_Géométrie_Ébrasement - Présent: no; Côté supérieur: no; Côté INFÉRIEUR: no; Épaisseur extérieure: 0 cm; Épaisseur latérale gauche: 0 cm; Épaisseur latérale droite: 0 cm; Épiasseur latérale supérieure: 0 cm; Épaisseur diagonale gauche: 0 cm; Épaisseur diagonale droite: 0 cm; Épaisseur diagonale inférieure: 0 cm; Épaisseur diagonale supérieure: 0 cm; Épaisseur intérieur: 0 cm; IFC_Pset_Géométrie_Seuil - Type: Aucun; Épaisseur: 0 cm; Épaisseur interne: 0 cm; Décalage séparation: 0 cm; Appui extérieur: 0 cm; Appui intérieur: 0 cm; Côté latéral externe: 0 cm; Côté latéral interne: 0 cm; IFC_Pset_Géométrie_Chambranle - Position: Aucun; Épaisseur Chambranle intérieur: 0 cm; Longueur Chambranle intérieur: 0 cm; Superposition Chambranle intérieur: 0 cm; Épaisseur Intrados: 0 cm; Épaisseur Chambranle extérieur: 0 cm; Largeur Chambranle extérieur: 0 cm; Superposition Chambranle extérieur: 0 cm; Épaisseur Intrados extérieur: 0 cm; Décalage séparation intrados: 0 cm; IFC_Pset_Géométrie_CORNICHE depuis profil - Position: Aucune; sets with these values: 2; IFC_Pset_Géométrie_CORNICHE Extérieure à partir d'un profil - Décalage: 0; Angle: 0 deg; Symétrie: no; Fermer: no; sets with these values: 2; IFC_Pset_Géométrie_BASE Extérieure à partir d'un profil - Angle: 0 deg; Symétrie: no; Côté: 0 cm; sets with these values: 2; IFC_Pset_Géométrie - Côté extérieur: 0; Invertir (dte/gche): no; Invertir (intérieur/extérieur): no; Forme: Arc + Rectangle; Largeur: 18.167 cm; Hauteur: 27.0965 cm; Hauteur 2: 0 cm; Rayon Arc: 9.08348 cm; Rayon Cercle: 0 cm; Demi-axe horizontal: 0 cm; Demi-axe vertical: 0 cm; IFC_Pset_Géométrie_GRILLE - décalage: 0 cm; Offset latéral: 0 cm; Décalage supérieur: 0 cm; Décalage inférieur: 0 cm; Nombre accrochages latéraux: 0; Nombre d'accrochages supérieurs: 0; Nombre accrochages inférieurs: 0; IFC_Pset_Géométrie_Niche - Présent: no; Stratigraphie: Paroi en béton armé [120,00]; Épaisseur: 12 cm; Alignement: Intérieur; Décalage: 0 cm; IFC_Pset_Système de Référence Altimétrique_INFÉRIEUR - NIVEAU: Niveau 1 (Niveau 1 2343); delta: 27.6724 cm; sous Niveau: <aucun>; IFC_Pset_Données Métré - Surface de l'Ouverture: 600 cm2; Surface de l'Ébrasement: 0 cm2; Surface du Seuil: 0 cm2; Surface du Seuil intérieur: 0 cm2; Volume du seuil: 0 cm3; Volume du seuil intérieur: 0 cm3; Surface de la Niche: 0 cm2; Surface de la Grille: 0 cm2; Volume de la Grille: 0 cm3
Baie 449448 | Niveau 1 | 449448 | 114 | 9006 | 1 | -746779066 | Description: _VTO_Baie; CTLG_EXTERNAL_LINK - 1, DocType: 9; 1, Tag: 211; 1, Crc: -732809594; IFC_Pset_Caractéristiques - ID: 449448; Numérotation: 120; Numéro niveau: 04; Titre niveau: Niveau 1; IFC_Pset_Géométrie_Allège - Hauteur: 0 cm; Stratigraphie: ...; Épaisseur: 0 cm; IFC_Pset_Géométrie_Ébrasement - Présent: no; Côté supérieur: no; Côté INFÉRIEUR: no; Épaisseur extérieure: 0 cm; Épaisseur latérale gauche: 0 cm; Épaisseur latérale droite: 0 cm; Épiasseur latérale supérieure: 0 cm; Épaisseur diagonale gauche: 0 cm; Épaisseur diagonale droite: 0 cm; Épaisseur diagonale inférieure: 0 cm; Épaisseur diagonale supérieure: 0 cm; Épaisseur intérieur: 0 cm; IFC_Pset_Géométrie_Seuil - Type: Aucun; Épaisseur: 0 cm; Épaisseur interne: 0 cm; Décalage séparation: 0 cm; Appui extérieur: 0 cm; Appui intérieur: 0 cm; Côté latéral externe: 0 cm; Côté latéral interne: 0 cm; IFC_Pset_Géométrie_Chambranle - Position: Aucun; Épaisseur Chambranle intérieur: 0 cm; Longueur Chambranle intérieur: 0 cm; Superposition Chambranle intérieur: 0 cm; Épaisseur Intrados: 0 cm; Épaisseur Chambranle extérieur: 0 cm; Largeur Chambranle extérieur: 0 cm; Superposition Chambranle extérieur: 0 cm; Épaisseur Intrados extérieur: 0 cm; Décalage séparation intrados: 0 cm; IFC_Pset_Géométrie_CORNICHE depuis profil - Position: Aucune; sets with these values: 2; IFC_Pset_Géométrie_CORNICHE Extérieure à partir d'un profil - Décalage: 0; Angle: 0 deg; Symétrie: no; Fermer: no; sets with these values: 2; IFC_Pset_Géométrie_BASE Extérieure à partir d'un profil - Angle: 0 deg; Symétrie: no; Côté: 0 cm; sets with these values: 2; IFC_Pset_Géométrie - Côté extérieur: 0; Invertir (dte/gche): no; Invertir (intérieur/extérieur): no; Forme: Arc + Rectangle; Largeur: 18.167 cm; Hauteur: 27.0965 cm; Hauteur 2: 0 cm; Rayon Arc: 9.08348 cm; Rayon Cercle: 0 cm; Demi-axe horizontal: 0 cm; Demi-axe vertical: 0 cm; IFC_Pset_Géométrie_GRILLE - décalage: 0 cm; Offset latéral: 0 cm; Décalage supérieur: 0 cm; Décalage inférieur: 0 cm; Nombre accrochages latéraux: 0; Nombre d'accrochages supérieurs: 0; Nombre accrochages inférieurs: 0; IFC_Pset_Géométrie_Niche - Présent: no; Stratigraphie: Paroi en béton armé [120,00]; Épaisseur: 12 cm; Alignement: Intérieur; Décalage: 0 cm; IFC_Pset_Système de Référence Altimétrique_INFÉRIEUR - NIVEAU: Niveau 1 (Niveau 1 2343); delta: 27.3907 cm; sous Niveau: <aucun>; IFC_Pset_Données Métré - Surface de l'Ouverture: 600 cm2; Surface de l'Ébrasement: 0 cm2; Surface du Seuil: 0 cm2; Surface du Seuil intérieur: 0 cm2; Volume du seuil: 0 cm3; Volume du seuil intérieur: 0 cm3; Surface de la Niche: 0 cm2; Surface de la Grille: 0 cm2; Volume de la Grille: 0 cm3
Baie 449449 | Niveau 1 | 449449 | 114 | 9006 | 1 | -746779066 | Description: _VTO_Baie; CTLG_EXTERNAL_LINK - 1, DocType: 9; 1, Tag: 211; 1, Crc: -732809594; IFC_Pset_Caractéristiques - ID: 449449; Numérotation: 121; Numéro niveau: 04; Titre niveau: Niveau 1; IFC_Pset_Géométrie_Allège - Hauteur: 0 cm; Stratigraphie: ...; Épaisseur: 0 cm; IFC_Pset_Géométrie_Ébrasement - Présent: no; Côté supérieur: no; Côté INFÉRIEUR: no; Épaisseur extérieure: 0 cm; Épaisseur latérale gauche: 0 cm; Épaisseur latérale droite: 0 cm; Épiasseur latérale supérieure: 0 cm; Épaisseur diagonale gauche: 0 cm; Épaisseur diagonale droite: 0 cm; Épaisseur diagonale inférieure: 0 cm; Épaisseur diagonale supérieure: 0 cm; Épaisseur intérieur: 0 cm; IFC_Pset_Géométrie_Seuil - Type: Aucun; Épaisseur: 0 cm; Épaisseur interne: 0 cm; Décalage séparation: 0 cm; Appui extérieur: 0 cm; Appui intérieur: 0 cm; Côté latéral externe: 0 cm; Côté latéral interne: 0 cm; IFC_Pset_Géométrie_Chambranle - Position: Aucun; Épaisseur Chambranle intérieur: 0 cm; Longueur Chambranle intérieur: 0 cm; Superposition Chambranle intérieur: 0 cm; Épaisseur Intrados: 0 cm; Épaisseur Chambranle extérieur: 0 cm; Largeur Chambranle extérieur: 0 cm; Superposition Chambranle extérieur: 0 cm; Épaisseur Intrados extérieur: 0 cm; Décalage séparation intrados: 0 cm; IFC_Pset_Géométrie_CORNICHE depuis profil - Position: Aucune; sets with these values: 2; IFC_Pset_Géométrie_CORNICHE Extérieure à partir d'un profil - Décalage: 0; Angle: 0 deg; Symétrie: no; Fermer: no; sets with these values: 2; IFC_Pset_Géométrie_BASE Extérieure à partir d'un profil - Angle: 0 deg; Symétrie: no; Côté: 0 cm; sets with these values: 2; IFC_Pset_Géométrie - Côté extérieur: 0; Invertir (dte/gche): no; Invertir (intérieur/extérieur): no; Forme: Arc + Rectangle; Largeur: 18.167 cm; Hauteur: 27.0965 cm; Hauteur 2: 0 cm; Rayon Arc: 9.08348 cm; Rayon Cercle: 0 cm; Demi-axe horizontal: 0 cm; Demi-axe vertical: 0 cm; IFC_Pset_Géométrie_GRILLE - décalage: 0 cm; Offset latéral: 0 cm; Décalage supérieur: 0 cm; Décalage inférieur: 0 cm; Nombre accrochages latéraux: 0; Nombre d'accrochages supérieurs: 0; Nombre accrochages inférieurs: 0; IFC_Pset_Géométrie_Niche - Présent: no; Stratigraphie: Paroi en béton armé [120,00]; Épaisseur: 12 cm; Alignement: Intérieur; Décalage: 0 cm; IFC_Pset_Système de Référence Altimétrique_INFÉRIEUR - NIVEAU: Niveau 1 (Niveau 1 2343); delta: 27.3907 cm; sous Niveau: <aucun>; IFC_Pset_Données Métré - Surface de l'Ouverture: 600 cm2; Surface de l'Ébrasement: 0 cm2; Surface du Seuil: 0 cm2; Surface du Seuil intérieur: 0 cm2; Volume du seuil: 0 cm3; Volume du seuil intérieur: 0 cm3; Surface de la Niche: 0 cm2; Surface de la Grille: 0 cm2; Volume de la Grille: 0 cm3
Baie 449464 | Niveau 1 | 449464 | 114 | 9006 | 1 | -746779066 | Description: _VTO_Baie; CTLG_EXTERNAL_LINK - 1, DocType: 9; 1, Tag: 211; 1, Crc: -732809594; IFC_Pset_Caractéristiques - ID: 449464; Numérotation: 126; Numéro niveau: 04; Titre niveau: Niveau 1; IFC_Pset_Géométrie_Allège - Hauteur: 0 cm; Stratigraphie: ...; Épaisseur: 0 cm; IFC_Pset_Géométrie_Ébrasement - Présent: no; Côté supérieur: no; Côté INFÉRIEUR: no; Épaisseur extérieure: 0 cm; Épaisseur latérale gauche: 0 cm; Épaisseur latérale droite: 0 cm; Épiasseur latérale supérieure: 0 cm; Épaisseur diagonale gauche: 0 cm; Épaisseur diagonale droite: 0 cm; Épaisseur diagonale inférieure: 0 cm; Épaisseur diagonale supérieure: 0 cm; Épaisseur intérieur: 0 cm; IFC_Pset_Géométrie_Seuil - Type: Aucun; Épaisseur: 0 cm; Épaisseur interne: 0 cm; Décalage séparation: 0 cm; Appui extérieur: 0 cm; Appui intérieur: 0 cm; Côté latéral externe: 0 cm; Côté latéral interne: 0 cm; IFC_Pset_Géométrie_Chambranle - Position: Aucun; Épaisseur Chambranle intérieur: 0 cm; Longueur Chambranle intérieur: 0 cm; Superposition Chambranle intérieur: 0 cm; Épaisseur Intrados: 0 cm; Épaisseur Chambranle extérieur: 0 cm; Largeur Chambranle extérieur: 0 cm; Superposition Chambranle extérieur: 0 cm; Épaisseur Intrados extérieur: 0 cm; Décalage séparation intrados: 0 cm; IFC_Pset_Géométrie_CORNICHE depuis profil - Position: Aucune; sets with these values: 2; IFC_Pset_Géométrie_CORNICHE Extérieure à partir d'un profil - Décalage: 0; Angle: 0 deg; Symétrie: no; Fermer: no; sets with these values: 2; IFC_Pset_Géométrie_BASE Extérieure à partir d'un profil - Angle: 0 deg; Symétrie: no; Côté: 0 cm; sets with these values: 2; IFC_Pset_Géométrie - Côté extérieur: 0; Invertir (dte/gche): no; Invertir (intérieur/extérieur): no; Forme: Arc + Rectangle; Largeur: 18.167 cm; Hauteur: 27.0965 cm; Hauteur 2: 0 cm; Rayon Arc: 9.08348 cm; Rayon Cercle: 0 cm; Demi-axe horizontal: 0 cm; Demi-axe vertical: 0 cm; IFC_Pset_Géométrie_GRILLE - décalage: 0 cm; Offset latéral: 0 cm; Décalage supérieur: 0 cm; Décalage inférieur: 0 cm; Nombre accrochages latéraux: 0; Nombre d'accrochages supérieurs: 0; Nombre accrochages inférieurs: 0; IFC_Pset_Géométrie_Niche - Présent: no; Stratigraphie: Paroi en béton armé [120,00]; Épaisseur: 12 cm; Alignement: Intérieur; Décalage: 0 cm; IFC_Pset_Système de Référence Altimétrique_INFÉRIEUR - NIVEAU: Niveau 1 (Niveau 1 2343); delta: 27.3907 cm; sous Niveau: <aucun>; IFC_Pset_Données Métré - Surface de l'Ouverture: 600 cm2; Surface de l'Ébrasement: 0 cm2; Surface du Seuil: 0 cm2; Surface du Seuil intérieur: 0 cm2; Volume du seuil: 0 cm3; Volume du seuil intérieur: 0 cm3; Surface de la Niche: 0 cm2; Surface de la Grille: 0 cm2; Volume de la Grille: 0 cm3
Baie 449460 | Niveau 1 | 449460 | 114 | 9006 | 1 | -746779066 | Description: _VTO_Baie; CTLG_EXTERNAL_LINK - 1, DocType: 9; 1, Tag: 211; 1, Crc: -732809594; IFC_Pset_Caractéristiques - ID: 449460; Numérotation: 122; Numéro niveau: 04; Titre niveau: Niveau 1; IFC_Pset_Géométrie_Allège - Hauteur: 0 cm; Stratigraphie: ...; Épaisseur: 0 cm; IFC_Pset_Géométrie_Ébrasement - Présent: no; Côté supérieur: no; Côté INFÉRIEUR: no; Épaisseur extérieure: 0 cm; Épaisseur latérale gauche: 0 cm; Épaisseur latérale droite: 0 cm; Épiasseur latérale supérieure: 0 cm; Épaisseur diagonale gauche: 0 cm; Épaisseur diagonale droite: 0 cm; Épaisseur diagonale inférieure: 0 cm; Épaisseur diagonale supérieure: 0 cm; Épaisseur intérieur: 0 cm; IFC_Pset_Géométrie_Seuil - Type: Aucun; Épaisseur: 0 cm; Épaisseur interne: 0 cm; Décalage séparation: 0 cm; Appui extérieur: 0 cm; Appui intérieur: 0 cm; Côté latéral externe: 0 cm; Côté latéral interne: 0 cm; IFC_Pset_Géométrie_Chambranle - Position: Aucun; Épaisseur Chambranle intérieur: 0 cm; Longueur Chambranle intérieur: 0 cm; Superposition Chambranle intérieur: 0 cm; Épaisseur Intrados: 0 cm; Épaisseur Chambranle extérieur: 0 cm; Largeur Chambranle extérieur: 0 cm; Superposition Chambranle extérieur: 0 cm; Épaisseur Intrados extérieur: 0 cm; Décalage séparation intrados: 0 cm; IFC_Pset_Géométrie_CORNICHE depuis profil - Position: Aucune; sets with these values: 2; IFC_Pset_Géométrie_CORNICHE Extérieure à partir d'un profil - Décalage: 0; Angle: 0 deg; Symétrie: no; Fermer: no; sets with these values: 2; IFC_Pset_Géométrie_BASE Extérieure à partir d'un profil - Angle: 0 deg; Symétrie: no; Côté: 0 cm; sets with these values: 2; IFC_Pset_Géométrie - Côté extérieur: 0; Invertir (dte/gche): no; Invertir (intérieur/extérieur): no; Forme: Arc + Rectangle; Largeur: 18.167 cm; Hauteur: 27.0965 cm; Hauteur 2: 0 cm; Rayon Arc: 9.08348 cm; Rayon Cercle: 0 cm; Demi-axe horizontal: 0 cm; Demi-axe vertical: 0 cm; IFC_Pset_Géométrie_GRILLE - décalage: 0 cm; Offset latéral: 0 cm; Décalage supérieur: 0 cm; Décalage inférieur: 0 cm; Nombre accrochages latéraux: 0; Nombre d'accrochages supérieurs: 0; Nombre accrochages inférieurs: 0; IFC_Pset_Géométrie_Niche - Présent: no; Stratigraphie: Paroi en béton armé [120,00]; Épaisseur: 12 cm; Alignement: Intérieur; Décalage: 0 cm; IFC_Pset_Système de Référence Altimétrique_INFÉRIEUR - NIVEAU: Niveau 1 (Niveau 1 2343); delta: 27.6724 cm; sous Niveau: <aucun>; IFC_Pset_Données Métré - Surface de l'Ouverture: 600 cm2; Surface de l'Ébrasement: 0 cm2; Surface du Seuil: 0 cm2; Surface du Seuil intérieur: 0 cm2; Volume du seuil: 0 cm3; Volume du seuil intérieur: 0 cm3; Surface de la Niche: 0 cm2; Surface de la Grille: 0 cm2; Volume de la Grille: 0 cm3
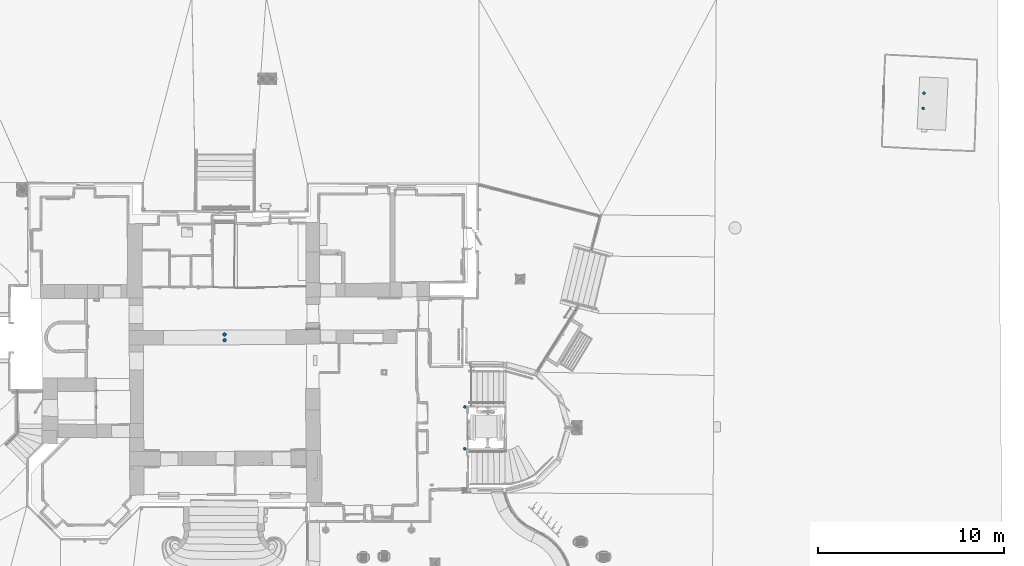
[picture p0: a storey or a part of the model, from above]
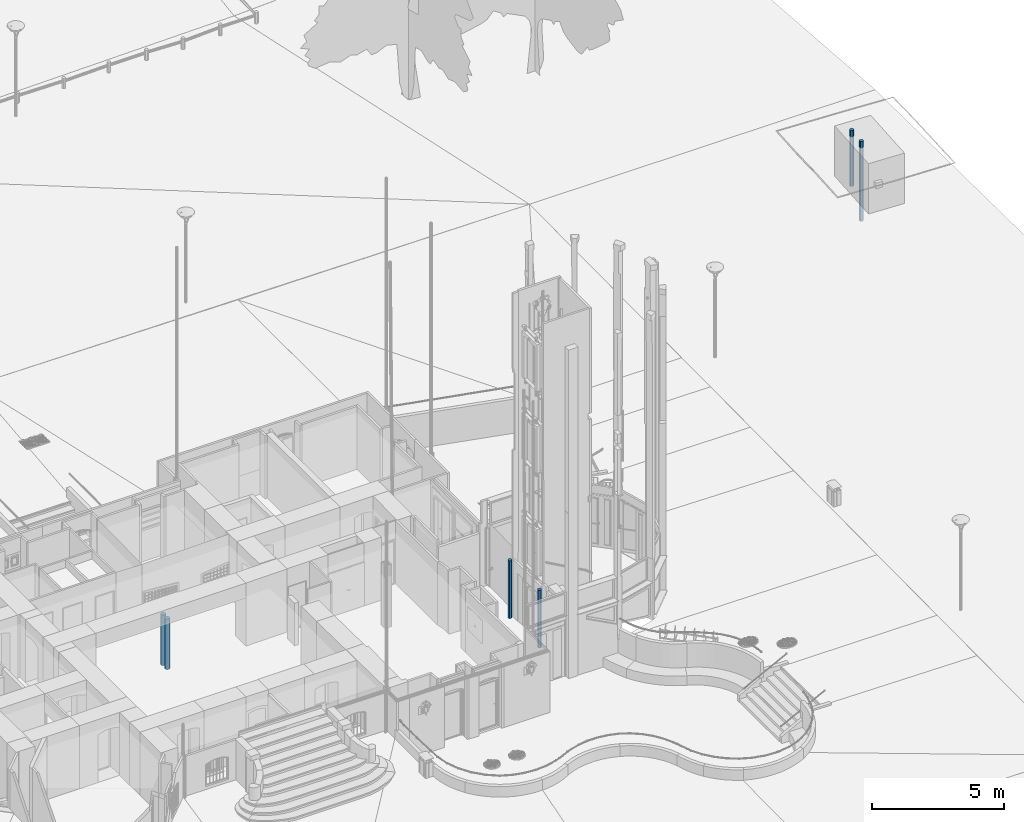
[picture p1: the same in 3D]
Properties of the parts of a building model (IFC2X3), part 13 of 37

# IfcOpeningElement: Opening (367)
Name | In | __RECOGNIZE__, ID | TPLG | TPLG_OD | GENERATE | 0, Crc
Baie 449461 | Niveau 1 | 449461 | 114 | 9006 | 1 | -746779066 | Description: _VTO_Baie; CTLG_EXTERNAL_LINK - 1, DocType: 9; 1, Tag: 211; 1, Crc: -732809594; IFC_Pset_Caractéristiques - ID: 449461; Numérotation: 123; Numéro niveau: 04; Titre niveau: Niveau 1; IFC_Pset_Géométrie_Allège - Hauteur: 0 cm; Stratigraphie: ...; Épaisseur: 0 cm; IFC_Pset_Géométrie_Ébrasement - Présent: no; Côté supérieur: no; Côté INFÉRIEUR: no; Épaisseur extérieure: 0 cm; Épaisseur latérale gauche: 0 cm; Épaisseur latérale droite: 0 cm; Épiasseur latérale supérieure: 0 cm; Épaisseur diagonale gauche: 0 cm; Épaisseur diagonale droite: 0 cm; Épaisseur diagonale inférieure: 0 cm; Épaisseur diagonale supérieure: 0 cm; Épaisseur intérieur: 0 cm; IFC_Pset_Géométrie_Seuil - Type: Aucun; Épaisseur: 0 cm; Épaisseur interne: 0 cm; Décalage séparation: 0 cm; Appui extérieur: 0 cm; Appui intérieur: 0 cm; Côté latéral externe: 0 cm; Côté latéral interne: 0 cm; IFC_Pset_Géométrie_Chambranle - Position: Aucun; Épaisseur Chambranle intérieur: 0 cm; Longueur Chambranle intérieur: 0 cm; Superposition Chambranle intérieur: 0 cm; Épaisseur Intrados: 0 cm; Épaisseur Chambranle extérieur: 0 cm; Largeur Chambranle extérieur: 0 cm; Superposition Chambranle extérieur: 0 cm; Épaisseur Intrados extérieur: 0 cm; Décalage séparation intrados: 0 cm; IFC_Pset_Géométrie_CORNICHE depuis profil - Position: Aucune; sets with these values: 2; IFC_Pset_Géométrie_CORNICHE Extérieure à partir d'un profil - Décalage: 0; Angle: 0 deg; Symétrie: no; Fermer: no; sets with these values: 2; IFC_Pset_Géométrie_BASE Extérieure à partir d'un profil - Angle: 0 deg; Symétrie: no; Côté: 0 cm; sets with these values: 2; IFC_Pset_Géométrie - Côté extérieur: 0; Invertir (dte/gche): no; Invertir (intérieur/extérieur): no; Forme: Arc + Rectangle; Largeur: 18.167 cm; Hauteur: 27.0965 cm; Hauteur 2: 0 cm; Rayon Arc: 9.08348 cm; Rayon Cercle: 0 cm; Demi-axe horizontal: 0 cm; Demi-axe vertical: 0 cm; IFC_Pset_Géométrie_GRILLE - décalage: 0 cm; Offset latéral: 0 cm; Décalage supérieur: 0 cm; Décalage inférieur: 0 cm; Nombre accrochages latéraux: 0; Nombre d'accrochages supérieurs: 0; Nombre accrochages inférieurs: 0; IFC_Pset_Géométrie_Niche - Présent: no; Stratigraphie: Paroi en béton armé [120,00]; Épaisseur: 12 cm; Alignement: Intérieur; Décalage: 0 cm; IFC_Pset_Système de Référence Altimétrique_INFÉRIEUR - NIVEAU: Niveau 1 (Niveau 1 2343); delta: 27.6724 cm; sous Niveau: <aucun>; IFC_Pset_Données Métré - Surface de l'Ouverture: 600 cm2; Surface de l'Ébrasement: 0 cm2; Surface du Seuil: 0 cm2; Surface du Seuil intérieur: 0 cm2; Volume du seuil: 0 cm3; Volume du seuil intérieur: 0 cm3; Surface de la Niche: 0 cm2; Surface de la Grille: 0 cm2; Volume de la Grille: 0 cm3
Baie 449463 | Niveau 1 | 449463 | 114 | 9006 | 1 | -746779066 | Description: _VTO_Baie; CTLG_EXTERNAL_LINK - 1, DocType: 9; 1, Tag: 211; 1, Crc: -732809594; IFC_Pset_Caractéristiques - ID: 449463; Numérotation: 125; Numéro niveau: 04; Titre niveau: Niveau 1; IFC_Pset_Géométrie_Allège - Hauteur: 0 cm; Stratigraphie: ...; Épaisseur: 0 cm; IFC_Pset_Géométrie_Ébrasement - Présent: no; Côté supérieur: no; Côté INFÉRIEUR: no; Épaisseur extérieure: 0 cm; Épaisseur latérale gauche: 0 cm; Épaisseur latérale droite: 0 cm; Épiasseur latérale supérieure: 0 cm; Épaisseur diagonale gauche: 0 cm; Épaisseur diagonale droite: 0 cm; Épaisseur diagonale inférieure: 0 cm; Épaisseur diagonale supérieure: 0 cm; Épaisseur intérieur: 0 cm; IFC_Pset_Géométrie_Seuil - Type: Aucun; Épaisseur: 0 cm; Épaisseur interne: 0 cm; Décalage séparation: 0 cm; Appui extérieur: 0 cm; Appui intérieur: 0 cm; Côté latéral externe: 0 cm; Côté latéral interne: 0 cm; IFC_Pset_Géométrie_Chambranle - Position: Aucun; Épaisseur Chambranle intérieur: 0 cm; Longueur Chambranle intérieur: 0 cm; Superposition Chambranle intérieur: 0 cm; Épaisseur Intrados: 0 cm; Épaisseur Chambranle extérieur: 0 cm; Largeur Chambranle extérieur: 0 cm; Superposition Chambranle extérieur: 0 cm; Épaisseur Intrados extérieur: 0 cm; Décalage séparation intrados: 0 cm; IFC_Pset_Géométrie_CORNICHE depuis profil - Position: Aucune; sets with these values: 2; IFC_Pset_Géométrie_CORNICHE Extérieure à partir d'un profil - Décalage: 0; Angle: 0 deg; Symétrie: no; Fermer: no; sets with these values: 2; IFC_Pset_Géométrie_BASE Extérieure à partir d'un profil - Angle: 0 deg; Symétrie: no; Côté: 0 cm; sets with these values: 2; IFC_Pset_Géométrie - Côté extérieur: 0; Invertir (dte/gche): no; Invertir (intérieur/extérieur): no; Forme: Arc + Rectangle; Largeur: 18.167 cm; Hauteur: 27.0965 cm; Hauteur 2: 0 cm; Rayon Arc: 9.08348 cm; Rayon Cercle: 0 cm; Demi-axe horizontal: 0 cm; Demi-axe vertical: 0 cm; IFC_Pset_Géométrie_GRILLE - décalage: 0 cm; Offset latéral: 0 cm; Décalage supérieur: 0 cm; Décalage inférieur: 0 cm; Nombre accrochages latéraux: 0; Nombre d'accrochages supérieurs: 0; Nombre accrochages inférieurs: 0; IFC_Pset_Géométrie_Niche - Présent: no; Stratigraphie: Paroi en béton armé [120,00]; Épaisseur: 12 cm; Alignement: Intérieur; Décalage: 0 cm; IFC_Pset_Système de Référence Altimétrique_INFÉRIEUR - NIVEAU: Niveau 1 (Niveau 1 2343); delta: 27.3907 cm; sous Niveau: <aucun>; IFC_Pset_Données Métré - Surface de l'Ouverture: 600 cm2; Surface de l'Ébrasement: 0 cm2; Surface du Seuil: 0 cm2; Surface du Seuil intérieur: 0 cm2; Volume du seuil: 0 cm3; Volume du seuil intérieur: 0 cm3; Surface de la Niche: 0 cm2; Surface de la Grille: 0 cm2; Volume de la Grille: 0 cm3
Baie 449462 | Niveau 1 | 449462 | 114 | 9006 | 1 | -746779066 | Description: _VTO_Baie; CTLG_EXTERNAL_LINK - 1, DocType: 9; 1, Tag: 211; 1, Crc: -732809594; IFC_Pset_Caractéristiques - ID: 449462; Numérotation: 124; Numéro niveau: 04; Titre niveau: Niveau 1; IFC_Pset_Géométrie_Allège - Hauteur: 0 cm; Stratigraphie: ...; Épaisseur: 0 cm; IFC_Pset_Géométrie_Ébrasement - Présent: no; Côté supérieur: no; Côté INFÉRIEUR: no; Épaisseur extérieure: 0 cm; Épaisseur latérale gauche: 0 cm; Épaisseur latérale droite: 0 cm; Épiasseur latérale supérieure: 0 cm; Épaisseur diagonale gauche: 0 cm; Épaisseur diagonale droite: 0 cm; Épaisseur diagonale inférieure: 0 cm; Épaisseur diagonale supérieure: 0 cm; Épaisseur intérieur: 0 cm; IFC_Pset_Géométrie_Seuil - Type: Aucun; Épaisseur: 0 cm; Épaisseur interne: 0 cm; Décalage séparation: 0 cm; Appui extérieur: 0 cm; Appui intérieur: 0 cm; Côté latéral externe: 0 cm; Côté latéral interne: 0 cm; IFC_Pset_Géométrie_Chambranle - Position: Aucun; Épaisseur Chambranle intérieur: 0 cm; Longueur Chambranle intérieur: 0 cm; Superposition Chambranle intérieur: 0 cm; Épaisseur Intrados: 0 cm; Épaisseur Chambranle extérieur: 0 cm; Largeur Chambranle extérieur: 0 cm; Superposition Chambranle extérieur: 0 cm; Épaisseur Intrados extérieur: 0 cm; Décalage séparation intrados: 0 cm; IFC_Pset_Géométrie_CORNICHE depuis profil - Position: Aucune; sets with these values: 2; IFC_Pset_Géométrie_CORNICHE Extérieure à partir d'un profil - Décalage: 0; Angle: 0 deg; Symétrie: no; Fermer: no; sets with these values: 2; IFC_Pset_Géométrie_BASE Extérieure à partir d'un profil - Angle: 0 deg; Symétrie: no; Côté: 0 cm; sets with these values: 2; IFC_Pset_Géométrie - Côté extérieur: 0; Invertir (dte/gche): no; Invertir (intérieur/extérieur): no; Forme: Arc + Rectangle; Largeur: 18.167 cm; Hauteur: 27.0965 cm; Hauteur 2: 0 cm; Rayon Arc: 9.08348 cm; Rayon Cercle: 0 cm; Demi-axe horizontal: 0 cm; Demi-axe vertical: 0 cm; IFC_Pset_Géométrie_GRILLE - décalage: 0 cm; Offset latéral: 0 cm; Décalage supérieur: 0 cm; Décalage inférieur: 0 cm; Nombre accrochages latéraux: 0; Nombre d'accrochages supérieurs: 0; Nombre accrochages inférieurs: 0; IFC_Pset_Géométrie_Niche - Présent: no; Stratigraphie: Paroi en béton armé [120,00]; Épaisseur: 12 cm; Alignement: Intérieur; Décalage: 0 cm; IFC_Pset_Système de Référence Altimétrique_INFÉRIEUR - NIVEAU: Niveau 1 (Niveau 1 2343); delta: 27.6724 cm; sous Niveau: <aucun>; IFC_Pset_Données Métré - Surface de l'Ouverture: 600 cm2; Surface de l'Ébrasement: 0 cm2; Surface du Seuil: 0 cm2; Surface du Seuil intérieur: 0 cm2; Volume du seuil: 0 cm3; Volume du seuil intérieur: 0 cm3; Surface de la Niche: 0 cm2; Surface de la Grille: 0 cm2; Volume de la Grille: 0 cm3
4294966533_11 | Niveau 1 | -763 | 2002 | 2002 | 0 | -1292786862
4294966532_11 | Niveau 1 | -764 | 2002 | 2002 | 0 | -1292786862
4294966531_11 | Niveau 1 | -765 | 2002 | 2002 | 0 | -1292786862
4294966530_11 | Niveau 1 | -766 | 2002 | 2002 | 0 | -1292786862
4294966543_11 | Niveau 1 | -753 | 2002 | 2002 | 0 | -1292786862
4294966534_11 | Niveau 1 | -762 | 2002 | 2002 | 0 | -1292786862
4294966536_11 | Niveau 1 | -760 | 2002 | 2002 | 0 | -1292786862
4294966537_11 | Niveau 1 | -759 | 2002 | 2002 | 0 | -1292786862
Baie 427162 | Niveau 1 | 427162 | 114 | 9006 | 1 | -746779066 | Description: _VTO_Baie; CTLG_EXTERNAL_LINK - 1, DocType: 9; 1, Tag: 211; 1, Crc: -732809594; IFC_Pset_Caractéristiques - ID: 427162; Numérotation: 097; Numéro niveau: 04; Titre niveau: Niveau 1; IFC_Pset_Géométrie_Allège - Hauteur: 0 cm; Stratigraphie: ...; Épaisseur: 0 cm; IFC_Pset_Géométrie_Ébrasement - Présent: yes; Côté supérieur: no; Côté INFÉRIEUR: no; Épaisseur extérieure: 11 cm; Épaisseur latérale gauche: 3 cm; Épaisseur latérale droite: 3 cm; Épiasseur latérale supérieure: 3 cm; Épaisseur diagonale gauche: 0 cm; Épaisseur diagonale droite: 0 cm; Épaisseur diagonale inférieure: 0 cm; Épaisseur diagonale supérieure: 0 cm; Épaisseur intérieur: 0 cm; Données: [a : 110,00; b: 30,00; c: 0,00; d: 0,00] mm; IFC_Pset_Géométrie_Seuil - Type: Aucun; Épaisseur: 0 cm; Épaisseur interne: 0 cm; Décalage séparation: 0 cm; Appui extérieur: 0 cm; Appui intérieur: 0 cm; Côté latéral externe: 0 cm; Côté latéral interne: 0 cm; IFC_Pset_Géométrie_Chambranle - Position: Aucun; Épaisseur Chambranle intérieur: 0 cm; Longueur Chambranle intérieur: 0 cm; Superposition Chambranle intérieur: 0 cm; Épaisseur Intrados: 0 cm; Épaisseur Chambranle extérieur: 0 cm; Largeur Chambranle extérieur: 0 cm; Superposition Chambranle extérieur: 0 cm; Épaisseur Intrados extérieur: 0 cm; Décalage séparation intrados: 0 cm; IFC_Pset_Géométrie_CORNICHE depuis profil - Position: Aucune; sets with these values: 2; IFC_Pset_Géométrie_CORNICHE Extérieure à partir d'un profil - Décalage: 0; Angle: 0 deg; Symétrie: no; Fermer: no; sets with these values: 2; IFC_Pset_Géométrie_BASE Extérieure à partir d'un profil - Angle: 0 deg; Symétrie: no; Côté: 0 cm; sets with these values: 2; IFC_Pset_Géométrie - Côté extérieur: 1; Invertir (dte/gche): no; Invertir (intérieur/extérieur): yes; Forme: Rectangle; Largeur: 109.862 cm; Hauteur: 246.996 cm; Hauteur 2: 0 cm; Rayon Arc: 0 cm; Rayon Cercle: 0 cm; Demi-axe horizontal: 0 cm; Demi-axe vertical: 0 cm; IFC_Pset_Géométrie_GRILLE - décalage: 0 cm; Offset latéral: 0 cm; Décalage supérieur: 0 cm; Décalage inférieur: 0 cm; Nombre accrochages latéraux: 0; Nombre d'accrochages supérieurs: 0; Nombre accrochages inférieurs: 0; IFC_Pset_Géométrie_Niche - Présent: no; Stratigraphie: Paroi en béton armé [120,00]; Épaisseur: 12 cm; Alignement: Intérieur; Décalage: 0 cm; IFC_Pset_Système de Référence Altimétrique_INFÉRIEUR - NIVEAU: Niveau 1 (Niveau 1 2343); delta: 47.2092 cm; sous Niveau: <aucun>; IFC_Pset_Données Métré - Surface de l'Ouverture: 27100 cm2; Surface de l'Ébrasement: 8900 cm2; Surface du Seuil: 0 cm2; Surface du Seuil intérieur: 0 cm2; Volume du seuil: 0 cm3; Volume du seuil intérieur: 0 cm3; Surface de la Niche: 0 cm2; Surface de la Grille: 0 cm2; Volume de la Grille: 0 cm3
Baie 427163 | Niveau 1 | 427163 | 114 | 9006 | 1 | -746779066 | Description: _VTO_Baie; CTLG_EXTERNAL_LINK - 1, DocType: 9; 1, Tag: 211; 1, Crc: -732809594; IFC_Pset_Caractéristiques - ID: 427163; Numérotation: 098; Numéro niveau: 04; Titre niveau: Niveau 1; IFC_Pset_Géométrie_Allège - Hauteur: 0 cm; Stratigraphie: ...; Épaisseur: 0 cm; IFC_Pset_Géométrie_Ébrasement - Présent: yes; Côté supérieur: no; Côté INFÉRIEUR: no; Épaisseur extérieure: 11 cm; Épaisseur latérale gauche: 3 cm; Épaisseur latérale droite: 3 cm; Épiasseur latérale supérieure: 3 cm; Épaisseur diagonale gauche: 0 cm; Épaisseur diagonale droite: 0 cm; Épaisseur diagonale inférieure: 0 cm; Épaisseur diagonale supérieure: 0 cm; Épaisseur intérieur: 0 cm; Données: [a : 110,00; b: 30,00; c: 0,00; d: 0,00] mm; IFC_Pset_Géométrie_Seuil - Type: Aucun; Épaisseur: 0 cm; Épaisseur interne: 0 cm; Décalage séparation: 0 cm; Appui extérieur: 0 cm; Appui intérieur: 0 cm; Côté latéral externe: 0 cm; Côté latéral interne: 0 cm; IFC_Pset_Géométrie_Chambranle - Position: Aucun; Épaisseur Chambranle intérieur: 0 cm; Longueur Chambranle intérieur: 0 cm; Superposition Chambranle intérieur: 0 cm; Épaisseur Intrados: 0 cm; Épaisseur Chambranle extérieur: 0 cm; Largeur Chambranle extérieur: 0 cm; Superposition Chambranle extérieur: 0 cm; Épaisseur Intrados extérieur: 0 cm; Décalage séparation intrados: 0 cm; IFC_Pset_Géométrie_CORNICHE depuis profil - Position: Aucune; sets with these values: 2; IFC_Pset_Géométrie_CORNICHE Extérieure à partir d'un profil - Décalage: 0; Angle: 0 deg; Symétrie: no; Fermer: no; sets with these values: 2; IFC_Pset_Géométrie_BASE Extérieure à partir d'un profil - Angle: 0 deg; Symétrie: no; Côté: 0 cm; sets with these values: 2; IFC_Pset_Géométrie - Côté extérieur: 0; Invertir (dte/gche): no; Invertir (intérieur/extérieur): no; Forme: Rectangle; Largeur: 110.063 cm; Hauteur: 246.996 cm; Hauteur 2: 0 cm; Rayon Arc: 0 cm; Rayon Cercle: 0 cm; Demi-axe horizontal: 0 cm; Demi-axe vertical: 0 cm; IFC_Pset_Géométrie_GRILLE - décalage: 0 cm; Offset latéral: 0 cm; Décalage supérieur: 0 cm; Décalage inférieur: 0 cm; Nombre accrochages latéraux: 0; Nombre d'accrochages supérieurs: 0; Nombre accrochages inférieurs: 0; IFC_Pset_Géométrie_Niche - Présent: no; Stratigraphie: Paroi en béton armé [120,00]; Épaisseur: 12 cm; Alignement: Intérieur; Décalage: 0 cm; IFC_Pset_Système de Référence Altimétrique_INFÉRIEUR - NIVEAU: Niveau 1 (Niveau 1 2343); delta: 46.6696 cm; sous Niveau: <aucun>; IFC_Pset_Données Métré - Surface de l'Ouverture: 27200 cm2; Surface de l'Ébrasement: 8900 cm2; Surface du Seuil: 0 cm2; Surface du Seuil intérieur: 0 cm2; Volume du seuil: 0 cm3; Volume du seuil intérieur: 0 cm3; Surface de la Niche: 0 cm2; Surface de la Grille: 0 cm2; Volume de la Grille: 0 cm3
Baie 442184 | Niveau 1 | 442184 | 114 | 9006 | 1 | -746779066 | Description: _VTO_Baie; CTLG_EXTERNAL_LINK - 1, DocType: 9; 1, Tag: 211; 1, Crc: -732809594; IFC_Pset_Caractéristiques - ID: 442184; Numérotation: 103; Numéro niveau: 04; Titre niveau: Niveau 1; IFC_Pset_Géométrie_Allège - Hauteur: 0 cm; Stratigraphie: ...; Épaisseur: 0 cm; IFC_Pset_Géométrie_Ébrasement - Présent: no; Côté supérieur: no; Côté INFÉRIEUR: no; Épaisseur extérieure: 0 cm; Épaisseur latérale gauche: 0 cm; Épaisseur latérale droite: 0 cm; Épiasseur latérale supérieure: 0 cm; Épaisseur diagonale gauche: 0 cm; Épaisseur diagonale droite: 0 cm; Épaisseur diagonale inférieure: 0 cm; Épaisseur diagonale supérieure: 0 cm; Épaisseur intérieur: 0 cm; IFC_Pset_Géométrie_Seuil - Type: Aucun; Épaisseur: 0 cm; Épaisseur interne: 0 cm; Décalage séparation: 0 cm; Appui extérieur: 0 cm; Appui intérieur: 0 cm; Côté latéral externe: 0 cm; Côté latéral interne: 0 cm; IFC_Pset_Géométrie_Chambranle - Position: Aucun; Épaisseur Chambranle intérieur: 0 cm; Longueur Chambranle intérieur: 0 cm; Superposition Chambranle intérieur: 0 cm; Épaisseur Intrados: 0 cm; Épaisseur Chambranle extérieur: 0 cm; Largeur Chambranle extérieur: 0 cm; Superposition Chambranle extérieur: 0 cm; Épaisseur Intrados extérieur: 0 cm; Décalage séparation intrados: 0 cm; IFC_Pset_Géométrie_CORNICHE depuis profil - Position: Aucune; sets with these values: 2; IFC_Pset_Géométrie_CORNICHE Extérieure à partir d'un profil - Décalage: 0; Angle: 0 deg; Symétrie: no; Fermer: no; sets with these values: 2; IFC_Pset_Géométrie_BASE Extérieure à partir d'un profil - Angle: 0 deg; Symétrie: no; Côté: 0 cm; sets with these values: 2; IFC_Pset_Géométrie - Côté extérieur: 1; Invertir (dte/gche): no; Invertir (intérieur/extérieur): yes; Forme: Rectangle; Largeur: 110.797 cm; Hauteur: 291.3 cm; Hauteur 2: 0 cm; Rayon Arc: 0 cm; Rayon Cercle: 0 cm; Demi-axe horizontal: 0 cm; Demi-axe vertical: 0 cm; IFC_Pset_Géométrie_GRILLE - décalage: 0 cm; Offset latéral: 0 cm; Décalage supérieur: 0 cm; Décalage inférieur: 0 cm; Nombre accrochages latéraux: 0; Nombre d'accrochages supérieurs: 0; Nombre accrochages inférieurs: 0; IFC_Pset_Géométrie_Niche - Présent: no; Stratigraphie: Paroi en béton armé [120,00]; Épaisseur: 12 cm; Alignement: Intérieur; Décalage: 0 cm; IFC_Pset_Système de Référence Altimétrique_INFÉRIEUR - NIVEAU: Niveau 1 (Niveau 1 2343); delta: 0.0128504 cm; sous Niveau: <aucun>; IFC_Pset_Données Métré - Surface de l'Ouverture: 32300 cm2; Surface de l'Ébrasement: 0 cm2; Surface du Seuil: 0 cm2; Surface du Seuil intérieur: 0 cm2; Volume du seuil: 0 cm3; Volume du seuil intérieur: 0 cm3; Surface de la Niche: 0 cm2; Surface de la Grille: 0 cm2; Volume de la Grille: 0 cm3
Baie 442185 | Niveau 1 | 442185 | 114 | 9006 | 1 | -746779066 | Description: _VTO_Baie; CTLG_EXTERNAL_LINK - 1, DocType: 9; 1, Tag: 211; 1, Crc: -732809594; IFC_Pset_Caractéristiques - ID: 442185; Numérotation: 104; Numéro niveau: 04; Titre niveau: Niveau 1; IFC_Pset_Géométrie_Allège - Hauteur: 0 cm; Stratigraphie: ...; Épaisseur: 0 cm; IFC_Pset_Géométrie_Ébrasement - Présent: no; Côté supérieur: no; Côté INFÉRIEUR: no; Épaisseur extérieure: 0 cm; Épaisseur latérale gauche: 0 cm; Épaisseur latérale droite: 0 cm; Épiasseur latérale supérieure: 0 cm; Épaisseur diagonale gauche: 0 cm; Épaisseur diagonale droite: 0 cm; Épaisseur diagonale inférieure: 0 cm; Épaisseur diagonale supérieure: 0 cm; Épaisseur intérieur: 0 cm; IFC_Pset_Géométrie_Seuil - Type: Aucun; Épaisseur: 0 cm; Épaisseur interne: 0 cm; Décalage séparation: 0 cm; Appui extérieur: 0 cm; Appui intérieur: 0 cm; Côté latéral externe: 0 cm; Côté latéral interne: 0 cm; IFC_Pset_Géométrie_Chambranle - Position: Aucun; Épaisseur Chambranle intérieur: 0 cm; Longueur Chambranle intérieur: 0 cm; Superposition Chambranle intérieur: 0 cm; Épaisseur Intrados: 0 cm; Épaisseur Chambranle extérieur: 0 cm; Largeur Chambranle extérieur: 0 cm; Superposition Chambranle extérieur: 0 cm; Épaisseur Intrados extérieur: 0 cm; Décalage séparation intrados: 0 cm; IFC_Pset_Géométrie_CORNICHE depuis profil - Position: Aucune; sets with these values: 2; IFC_Pset_Géométrie_CORNICHE Extérieure à partir d'un profil - Décalage: 0; Angle: 0 deg; Symétrie: no; Fermer: no; sets with these values: 2; IFC_Pset_Géométrie_BASE Extérieure à partir d'un profil - Angle: 0 deg; Symétrie: no; Côté: 0 cm; sets with these values: 2; IFC_Pset_Géométrie - Côté extérieur: 1; Invertir (dte/gche): no; Invertir (intérieur/extérieur): yes; Forme: Rectangle; Largeur: 110.797 cm; Hauteur: 291.3 cm; Hauteur 2: 0 cm; Rayon Arc: 0 cm; Rayon Cercle: 0 cm; Demi-axe horizontal: 0 cm; Demi-axe vertical: 0 cm; IFC_Pset_Géométrie_GRILLE - décalage: 0 cm; Offset latéral: 0 cm; Décalage supérieur: 0 cm; Décalage inférieur: 0 cm; Nombre accrochages latéraux: 0; Nombre d'accrochages supérieurs: 0; Nombre accrochages inférieurs: 0; IFC_Pset_Géométrie_Niche - Présent: no; Stratigraphie: Paroi en béton armé [120,00]; Épaisseur: 12 cm; Alignement: Intérieur; Décalage: 0 cm; IFC_Pset_Système de Référence Altimétrique_INFÉRIEUR - NIVEAU: Niveau 1 (Niveau 1 2343); delta: 0.0128504 cm; sous Niveau: <aucun>; IFC_Pset_Données Métré - Surface de l'Ouverture: 32300 cm2; Surface de l'Ébrasement: 0 cm2; Surface du Seuil: 0 cm2; Surface du Seuil intérieur: 0 cm2; Volume du seuil: 0 cm3; Volume du seuil intérieur: 0 cm3; Surface de la Niche: 0 cm2; Surface de la Grille: 0 cm2; Volume de la Grille: 0 cm3
Baie 442165 | Niveau 1 | 442165 | 114 | 9006 | 1 | -746779066 | Description: _VTO_Baie; CTLG_EXTERNAL_LINK - 1, DocType: 9; 1, Tag: 211; 1, Crc: -732809594; IFC_Pset_Caractéristiques - ID: 442165; Numérotation: 099; Numéro niveau: 04; Titre niveau: Niveau 1; IFC_Pset_Géométrie_Allège - Hauteur: 0 cm; Stratigraphie: ...; Épaisseur: 0 cm; IFC_Pset_Géométrie_Ébrasement - Présent: no; Côté supérieur: no; Côté INFÉRIEUR: no; Épaisseur extérieure: 0 cm; Épaisseur latérale gauche: 0 cm; Épaisseur latérale droite: 0 cm; Épiasseur latérale supérieure: 0 cm; Épaisseur diagonale gauche: 0 cm; Épaisseur diagonale droite: 0 cm; Épaisseur diagonale inférieure: 0 cm; Épaisseur diagonale supérieure: 0 cm; Épaisseur intérieur: 0 cm; IFC_Pset_Géométrie_Seuil - Type: Aucun; Épaisseur: 0 cm; Épaisseur interne: 0 cm; Décalage séparation: 0 cm; Appui extérieur: 0 cm; Appui intérieur: 0 cm; Côté latéral externe: 0 cm; Côté latéral interne: 0 cm; IFC_Pset_Géométrie_Chambranle - Position: Aucun; Épaisseur Chambranle intérieur: 0 cm; Longueur Chambranle intérieur: 0 cm; Superposition Chambranle intérieur: 0 cm; Épaisseur Intrados: 0 cm; Épaisseur Chambranle extérieur: 0 cm; Largeur Chambranle extérieur: 0 cm; Superposition Chambranle extérieur: 0 cm; Épaisseur Intrados extérieur: 0 cm; Décalage séparation intrados: 0 cm; IFC_Pset_Géométrie_CORNICHE depuis profil - Position: Aucune; sets with these values: 2; IFC_Pset_Géométrie_CORNICHE Extérieure à partir d'un profil - Décalage: 0; Angle: 0 deg; Symétrie: no; Fermer: no; sets with these values: 2; IFC_Pset_Géométrie_BASE Extérieure à partir d'un profil - Angle: 0 deg; Symétrie: no; Côté: 0 cm; sets with these values: 2; IFC_Pset_Géométrie - Côté extérieur: 0; Invertir (dte/gche): no; Invertir (intérieur/extérieur): no; Forme: Arc + Rectangle; Largeur: 159.82 cm; Hauteur: 39.9088 cm; Hauteur 2: 0 cm; Rayon Arc: 21.9958 cm; Rayon Cercle: 0 cm; Demi-axe horizontal: 0 cm; Demi-axe vertical: 0 cm; IFC_Pset_Géométrie_GRILLE - décalage: 0 cm; Offset latéral: 0 cm; Décalage supérieur: 0 cm; Décalage inférieur: 0 cm; Nombre accrochages latéraux: 0; Nombre d'accrochages supérieurs: 0; Nombre accrochages inférieurs: 0; IFC_Pset_Géométrie_Niche - Présent: no; Stratigraphie: Paroi en béton armé [120,00]; Épaisseur: 12 cm; Alignement: Intérieur; Décalage: 0 cm; IFC_Pset_Système de Référence Altimétrique_INFÉRIEUR - NIVEAU: Niveau 1 (Niveau 1 2343); delta: 285 cm; sous Niveau: <aucun>; IFC_Pset_Données Métré - Surface de l'Ouverture: 8700 cm2; Surface de l'Ébrasement: 0 cm2; Surface du Seuil: 0 cm2; Surface du Seuil intérieur: 0 cm2; Volume du seuil: 0 cm3; Volume du seuil intérieur: 0 cm3; Surface de la Niche: 0 cm2; Surface de la Grille: 0 cm2; Volume de la Grille: 0 cm3
Baie 442183 | Niveau 1 | 442183 | 114 | 9006 | 1 | -746779066 | Description: _VTO_Baie; CTLG_EXTERNAL_LINK - 1, DocType: 9; 1, Tag: 211; 1, Crc: -732809594; IFC_Pset_Caractéristiques - ID: 442183; Numérotation: 102; Numéro niveau: 04; Titre niveau: Niveau 1; IFC_Pset_Géométrie_Allège - Hauteur: 0 cm; Stratigraphie: ...; Épaisseur: 0 cm; IFC_Pset_Géométrie_Ébrasement - Présent: no; Côté supérieur: no; Côté INFÉRIEUR: no; Épaisseur extérieure: 0 cm; Épaisseur latérale gauche: 0 cm; Épaisseur latérale droite: 0 cm; Épiasseur latérale supérieure: 0 cm; Épaisseur diagonale gauche: 0 cm; Épaisseur diagonale droite: 0 cm; Épaisseur diagonale inférieure: 0 cm; Épaisseur diagonale supérieure: 0 cm; Épaisseur intérieur: 0 cm; IFC_Pset_Géométrie_Seuil - Type: Aucun; Épaisseur: 0 cm; Épaisseur interne: 0 cm; Décalage séparation: 0 cm; Appui extérieur: 0 cm; Appui intérieur: 0 cm; Côté latéral externe: 0 cm; Côté latéral interne: 0 cm; IFC_Pset_Géométrie_Chambranle - Position: Aucun; Épaisseur Chambranle intérieur: 0 cm; Longueur Chambranle intérieur: 0 cm; Superposition Chambranle intérieur: 0 cm; Épaisseur Intrados: 0 cm; Épaisseur Chambranle extérieur: 0 cm; Largeur Chambranle extérieur: 0 cm; Superposition Chambranle extérieur: 0 cm; Épaisseur Intrados extérieur: 0 cm; Décalage séparation intrados: 0 cm; IFC_Pset_Géométrie_CORNICHE depuis profil - Position: Aucune; sets with these values: 2; IFC_Pset_Géométrie_CORNICHE Extérieure à partir d'un profil - Décalage: 0; Angle: 0 deg; Symétrie: no; Fermer: no; sets with these values: 2; IFC_Pset_Géométrie_BASE Extérieure à partir d'un profil - Angle: 0 deg; Symétrie: no; Côté: 0 cm; sets with these values: 2; IFC_Pset_Géométrie - Côté extérieur: 1; Invertir (dte/gche): no; Invertir (intérieur/extérieur): yes; Forme: Rectangle; Largeur: 110.3 cm; Hauteur: 291.3 cm; Hauteur 2: 0 cm; Rayon Arc: 0 cm; Rayon Cercle: 0 cm; Demi-axe horizontal: 0 cm; Demi-axe vertical: 0 cm; IFC_Pset_Géométrie_GRILLE - décalage: 0 cm; Offset latéral: 0 cm; Décalage supérieur: 0 cm; Décalage inférieur: 0 cm; Nombre accrochages latéraux: 0; Nombre d'accrochages supérieurs: 0; Nombre accrochages inférieurs: 0; IFC_Pset_Géométrie_Niche - Présent: no; Stratigraphie: Paroi en béton armé [120,00]; Épaisseur: 12 cm; Alignement: Intérieur; Décalage: 0 cm; IFC_Pset_Système de Référence Altimétrique_INFÉRIEUR - NIVEAU: Niveau 1 (Niveau 1 2343); delta: 0.0128504 cm; sous Niveau: <aucun>; IFC_Pset_Données Métré - Surface de l'Ouverture: 32100 cm2; Surface de l'Ébrasement: 0 cm2; Surface du Seuil: 0 cm2; Surface du Seuil intérieur: 0 cm2; Volume du seuil: 0 cm3; Volume du seuil intérieur: 0 cm3; Surface de la Niche: 0 cm2; Surface de la Grille: 0 cm2; Volume de la Grille: 0 cm3
Baie 427148 | Niveau 1 | 427148 | 114 | 9006 | 1 | -746779066 | Description: _VTO_Baie; CTLG_EXTERNAL_LINK - 1, DocType: 9; 1, Tag: 211; 1, Crc: -732809594; IFC_Pset_Caractéristiques - ID: 427148; Numérotation: 092; Numéro niveau: 04; Titre niveau: Niveau 1; IFC_Pset_Géométrie_Allège - Hauteur: 0 cm; Stratigraphie: ...; Épaisseur: 0 cm; IFC_Pset_Géométrie_Ébrasement - Présent: yes; Côté supérieur: no; Côté INFÉRIEUR: no; Épaisseur extérieure: 11 cm; Épaisseur latérale gauche: 3 cm; Épaisseur latérale droite: 3 cm; Épiasseur latérale supérieure: 3 cm; Épaisseur diagonale gauche: 0 cm; Épaisseur diagonale droite: 0 cm; Épaisseur diagonale inférieure: 0 cm; Épaisseur diagonale supérieure: 0 cm; Épaisseur intérieur: 0 cm; Données: [a : 110,00; b: 30,00; c: 0,00; d: 0,00] mm; IFC_Pset_Géométrie_Seuil - Type: Aucun; Épaisseur: 0 cm; Épaisseur interne: 0 cm; Décalage séparation: 0 cm; Appui extérieur: 0 cm; Appui intérieur: 0 cm; Côté latéral externe: 0 cm; Côté latéral interne: 0 cm; IFC_Pset_Géométrie_Chambranle - Position: Aucun; Épaisseur Chambranle intérieur: 0 cm; Longueur Chambranle intérieur: 0 cm; Superposition Chambranle intérieur: 0 cm; Épaisseur Intrados: 0 cm; Épaisseur Chambranle extérieur: 0 cm; Largeur Chambranle extérieur: 0 cm; Superposition Chambranle extérieur: 0 cm; Épaisseur Intrados extérieur: 0 cm; Décalage séparation intrados: 0 cm; IFC_Pset_Géométrie_CORNICHE depuis profil - Position: Aucune; sets with these values: 2; IFC_Pset_Géométrie_CORNICHE Extérieure à partir d'un profil - Décalage: 0; Angle: 0 deg; Symétrie: no; Fermer: no; sets with these values: 2; IFC_Pset_Géométrie_BASE Extérieure à partir d'un profil - Angle: 0 deg; Symétrie: no; Côté: 0 cm; sets with these values: 2; IFC_Pset_Géométrie - Côté extérieur: 1; Invertir (dte/gche): no; Invertir (intérieur/extérieur): yes; Forme: Rectangle; Largeur: 109.644 cm; Hauteur: 248.196 cm; Hauteur 2: 0 cm; Rayon Arc: 0 cm; Rayon Cercle: 0 cm; Demi-axe horizontal: 0 cm; Demi-axe vertical: 0 cm; IFC_Pset_Géométrie_GRILLE - décalage: 0 cm; Offset latéral: 0 cm; Décalage supérieur: 0 cm; Décalage inférieur: 0 cm; Nombre accrochages latéraux: 0; Nombre d'accrochages supérieurs: 0; Nombre accrochages inférieurs: 0; IFC_Pset_Géométrie_Niche - Présent: no; Stratigraphie: Paroi en béton armé [120,00]; Épaisseur: 12 cm; Alignement: Intérieur; Décalage: 0 cm; IFC_Pset_Système de Référence Altimétrique_INFÉRIEUR - NIVEAU: Niveau 1 (Niveau 1 2343); delta: 46.5139 cm; sous Niveau: <aucun>; IFC_Pset_Données Métré - Surface de l'Ouverture: 27200 cm2; Surface de l'Ébrasement: 8900 cm2; Surface du Seuil: 0 cm2; Surface du Seuil intérieur: 0 cm2; Volume du seuil: 0 cm3; Volume du seuil intérieur: 0 cm3; Surface de la Niche: 0 cm2; Surface de la Grille: 0 cm2; Volume de la Grille: 0 cm3
Baie 427159 | Niveau 1 | 427159 | 114 | 9006 | 1 | -746779066 | Description: _VTO_Baie; CTLG_EXTERNAL_LINK - 1, DocType: 9; 1, Tag: 211; 1, Crc: -732809594; IFC_Pset_Caractéristiques - ID: 427159; Numérotation: 095; Numéro niveau: 04; Titre niveau: Niveau 1; IFC_Pset_Géométrie_Allège - Hauteur: 0 cm; Stratigraphie: ...; Épaisseur: 0 cm; IFC_Pset_Géométrie_Ébrasement - Présent: yes; Côté supérieur: no; Côté INFÉRIEUR: no; Épaisseur extérieure: 11 cm; Épaisseur latérale gauche: 3 cm; Épaisseur latérale droite: 3 cm; Épiasseur latérale supérieure: 3 cm; Épaisseur diagonale gauche: 0 cm; Épaisseur diagonale droite: 0 cm; Épaisseur diagonale inférieure: 0 cm; Épaisseur diagonale supérieure: 0 cm; Épaisseur intérieur: 0 cm; Données: [a : 110,00; b: 30,00; c: 0,00; d: 0,00] mm; IFC_Pset_Géométrie_Seuil - Type: Aucun; Épaisseur: 0 cm; Épaisseur interne: 0 cm; Décalage séparation: 0 cm; Appui extérieur: 0 cm; Appui intérieur: 0 cm; Côté latéral externe: 0 cm; Côté latéral interne: 0 cm; IFC_Pset_Géométrie_Chambranle - Position: Aucun; Épaisseur Chambranle intérieur: 0 cm; Longueur Chambranle intérieur: 0 cm; Superposition Chambranle intérieur: 0 cm; Épaisseur Intrados: 0 cm; Épaisseur Chambranle extérieur: 0 cm; Largeur Chambranle extérieur: 0 cm; Superposition Chambranle extérieur: 0 cm; Épaisseur Intrados extérieur: 0 cm; Décalage séparation intrados: 0 cm; IFC_Pset_Géométrie_CORNICHE depuis profil - Position: Aucune; sets with these values: 2; IFC_Pset_Géométrie_CORNICHE Extérieure à partir d'un profil - Décalage: 0; Angle: 0 deg; Symétrie: no; Fermer: no; sets with these values: 2; IFC_Pset_Géométrie_BASE Extérieure à partir d'un profil - Angle: 0 deg; Symétrie: no; Côté: 0 cm; sets with these values: 2; IFC_Pset_Géométrie - Côté extérieur: 1; Invertir (dte/gche): no; Invertir (intérieur/extérieur): yes; Forme: Rectangle; Largeur: 30.5157 cm; Hauteur: 156.276 cm; Hauteur 2: 0 cm; Rayon Arc: 0 cm; Rayon Cercle: 0 cm; Demi-axe horizontal: 0 cm; Demi-axe vertical: 0 cm; IFC_Pset_Géométrie_GRILLE - décalage: 0 cm; Offset latéral: 0 cm; Décalage supérieur: 0 cm; Décalage inférieur: 0 cm; Nombre accrochages latéraux: 0; Nombre d'accrochages supérieurs: 0; Nombre accrochages inférieurs: 0; IFC_Pset_Géométrie_Niche - Présent: no; Stratigraphie: Paroi en béton armé [120,00]; Épaisseur: 12 cm; Alignement: Intérieur; Décalage: 0 cm; IFC_Pset_Système de Référence Altimétrique_INFÉRIEUR - NIVEAU: Niveau 1 (Niveau 1 2343); delta: 138.887 cm; sous Niveau: <aucun>; IFC_Pset_Données Métré - Surface de l'Ouverture: 4800 cm2; Surface de l'Ébrasement: 5600 cm2; Surface du Seuil: 0 cm2; Surface du Seuil intérieur: 0 cm2; Volume du seuil: 0 cm3; Volume du seuil intérieur: 0 cm3; Surface de la Niche: 0 cm2; Surface de la Grille: 0 cm2; Volume de la Grille: 0 cm3
Baie 427161 | Niveau 1 | 427161 | 114 | 9006 | 1 | -746779066 | Description: _VTO_Baie; CTLG_EXTERNAL_LINK - 1, DocType: 9; 1, Tag: 211; 1, Crc: -732809594; IFC_Pset_Caractéristiques - ID: 427161; Numérotation: 096; Numéro niveau: 04; Titre niveau: Niveau 1; IFC_Pset_Géométrie_Allège - Hauteur: 0 cm; Stratigraphie: ...; Épaisseur: 0 cm; IFC_Pset_Géométrie_Ébrasement - Présent: yes; Côté supérieur: no; Côté INFÉRIEUR: no; Épaisseur extérieure: 11 cm; Épaisseur latérale gauche: 3 cm; Épaisseur latérale droite: 3 cm; Épiasseur latérale supérieure: 3 cm; Épaisseur diagonale gauche: 0 cm; Épaisseur diagonale droite: 0 cm; Épaisseur diagonale inférieure: 0 cm; Épaisseur diagonale supérieure: 0 cm; Épaisseur intérieur: 0 cm; Données: [a : 110,00; b: 30,00; c: 0,00; d: 0,00] mm; IFC_Pset_Géométrie_Seuil - Type: Aucun; Épaisseur: 0 cm; Épaisseur interne: 0 cm; Décalage séparation: 0 cm; Appui extérieur: 0 cm; Appui intérieur: 0 cm; Côté latéral externe: 0 cm; Côté latéral interne: 0 cm; IFC_Pset_Géométrie_Chambranle - Position: Aucun; Épaisseur Chambranle intérieur: 0 cm; Longueur Chambranle intérieur: 0 cm; Superposition Chambranle intérieur: 0 cm; Épaisseur Intrados: 0 cm; Épaisseur Chambranle extérieur: 0 cm; Largeur Chambranle extérieur: 0 cm; Superposition Chambranle extérieur: 0 cm; Épaisseur Intrados extérieur: 0 cm; Décalage séparation intrados: 0 cm; IFC_Pset_Géométrie_CORNICHE depuis profil - Position: Aucune; sets with these values: 2; IFC_Pset_Géométrie_CORNICHE Extérieure à partir d'un profil - Décalage: 0; Angle: 0 deg; Symétrie: no; Fermer: no; sets with these values: 2; IFC_Pset_Géométrie_BASE Extérieure à partir d'un profil - Angle: 0 deg; Symétrie: no; Côté: 0 cm; sets with these values: 2; IFC_Pset_Géométrie - Côté extérieur: 1; Invertir (dte/gche): no; Invertir (intérieur/extérieur): yes; Forme: Rectangle; Largeur: 30.6293 cm; Hauteur: 156.276 cm; Hauteur 2: 0 cm; Rayon Arc: 0 cm; Rayon Cercle: 0 cm; Demi-axe horizontal: 0 cm; Demi-axe vertical: 0 cm; IFC_Pset_Géométrie_GRILLE - décalage: 0 cm; Offset latéral: 0 cm; Décalage supérieur: 0 cm; Décalage inférieur: 0 cm; Nombre accrochages latéraux: 0; Nombre d'accrochages supérieurs: 0; Nombre accrochages inférieurs: 0; IFC_Pset_Géométrie_Niche - Présent: no; Stratigraphie: Paroi en béton armé [120,00]; Épaisseur: 12 cm; Alignement: Intérieur; Décalage: 0 cm; IFC_Pset_Système de Référence Altimétrique_INFÉRIEUR - NIVEAU: Niveau 1 (Niveau 1 2343); delta: 139.182 cm; sous Niveau: <aucun>; IFC_Pset_Données Métré - Surface de l'Ouverture: 4800 cm2; Surface de l'Ébrasement: 5600 cm2; Surface du Seuil: 0 cm2; Surface du Seuil intérieur: 0 cm2; Volume du seuil: 0 cm3; Volume du seuil intérieur: 0 cm3; Surface de la Niche: 0 cm2; Surface de la Grille: 0 cm2; Volume de la Grille: 0 cm3
Baie 426957 | Niveau 1 | 426957 | 114 | 9006 | 1 | -746779066 | Description: _VTO_Baie; CTLG_EXTERNAL_LINK - 1, DocType: 9; 1, Tag: 211; 1, Crc: -732809594; IFC_Pset_Caractéristiques - ID: 426957; Numérotation: 090; Numéro niveau: 04; Titre niveau: Niveau 1; IFC_Pset_Géométrie_Allège - Hauteur: 0 cm; Stratigraphie: ...; Épaisseur: 0 cm; IFC_Pset_Géométrie_Ébrasement - Présent: yes; Côté supérieur: no; Côté INFÉRIEUR: no; Épaisseur extérieure: 11 cm; Épaisseur latérale gauche: 3 cm; Épaisseur latérale droite: 3 cm; Épiasseur latérale supérieure: 3 cm; Épaisseur diagonale gauche: 0 cm; Épaisseur diagonale droite: 0 cm; Épaisseur diagonale inférieure: 0 cm; Épaisseur diagonale supérieure: 0 cm; Épaisseur intérieur: 0 cm; Données: [a : 110,00; b: 30,00; c: 0,00; d: 0,00] mm; IFC_Pset_Géométrie_Seuil - Type: Aucun; Épaisseur: 0 cm; Épaisseur interne: 0 cm; Décalage séparation: 0 cm; Appui extérieur: 0 cm; Appui intérieur: 0 cm; Côté latéral externe: 0 cm; Côté latéral interne: 0 cm; IFC_Pset_Géométrie_Chambranle - Position: Aucun; Épaisseur Chambranle intérieur: 0 cm; Longueur Chambranle intérieur: 0 cm; Superposition Chambranle intérieur: 0 cm; Épaisseur Intrados: 0 cm; Épaisseur Chambranle extérieur: 0 cm; Largeur Chambranle extérieur: 0 cm; Superposition Chambranle extérieur: 0 cm; Épaisseur Intrados extérieur: 0 cm; Décalage séparation intrados: 0 cm; IFC_Pset_Géométrie_CORNICHE depuis profil - Position: Aucune; sets with these values: 2; IFC_Pset_Géométrie_CORNICHE Extérieure à partir d'un profil - Décalage: 0; Angle: 0 deg; Symétrie: no; Fermer: no; sets with these values: 2; IFC_Pset_Géométrie_BASE Extérieure à partir d'un profil - Angle: 0 deg; Symétrie: no; Côté: 0 cm; sets with these values: 2; IFC_Pset_Géométrie - Côté extérieur: 0; Invertir (dte/gche): no; Invertir (intérieur/extérieur): no; Forme: Rectangle; Largeur: 109.609 cm; Hauteur: 247.973 cm; Hauteur 2: 0 cm; Rayon Arc: 0 cm; Rayon Cercle: 0 cm; Demi-axe horizontal: 0 cm; Demi-axe vertical: 0 cm; IFC_Pset_Géométrie_GRILLE - décalage: 0 cm; Offset latéral: 0 cm; Décalage supérieur: 0 cm; Décalage inférieur: 0 cm; Nombre accrochages latéraux: 0; Nombre d'accrochages supérieurs: 0; Nombre accrochages inférieurs: 0; IFC_Pset_Géométrie_Niche - Présent: no; Stratigraphie: Paroi en béton armé [120,00]; Épaisseur: 12 cm; Alignement: Intérieur; Décalage: 0 cm; IFC_Pset_Système de Référence Altimétrique_INFÉRIEUR - NIVEAU: Niveau 1 (Niveau 1 2343); delta: 46.404 cm; sous Niveau: <aucun>; IFC_Pset_Données Métré - Surface de l'Ouverture: 27200 cm2; Surface de l'Ébrasement: 8900 cm2; Surface du Seuil: 0 cm2; Surface du Seuil intérieur: 0 cm2; Volume du seuil: 0 cm3; Volume du seuil intérieur: 0 cm3; Surface de la Niche: 0 cm2; Surface de la Grille: 0 cm2; Volume de la Grille: 0 cm3
Baie 427050 | Niveau 1 | 427050 | 114 | 9006 | 1 | -746779066 | Description: _VTO_Baie; CTLG_EXTERNAL_LINK - 1, DocType: 9; 1, Tag: 211; 1, Crc: -732809594; IFC_Pset_Caractéristiques - ID: 427050; Numérotation: 091; Numéro niveau: 04; Titre niveau: Niveau 1; IFC_Pset_Géométrie_Allège - Hauteur: 0 cm; Stratigraphie: ...; Épaisseur: 0 cm; IFC_Pset_Géométrie_Ébrasement - Présent: yes; Côté supérieur: no; Côté INFÉRIEUR: no; Épaisseur extérieure: 11 cm; Épaisseur latérale gauche: 3 cm; Épaisseur latérale droite: 3 cm; Épiasseur latérale supérieure: 3 cm; Épaisseur diagonale gauche: 0 cm; Épaisseur diagonale droite: 0 cm; Épaisseur diagonale inférieure: 0 cm; Épaisseur diagonale supérieure: 0 cm; Épaisseur intérieur: 0 cm; Données: [a : 110,00; b: 30,00; c: 0,00; d: 0,00] mm; IFC_Pset_Géométrie_Seuil - Type: Aucun; Épaisseur: 0 cm; Épaisseur interne: 0 cm; Décalage séparation: 0 cm; Appui extérieur: 0 cm; Appui intérieur: 0 cm; Côté latéral externe: 0 cm; Côté latéral interne: 0 cm; IFC_Pset_Géométrie_Chambranle - Position: Aucun; Épaisseur Chambranle intérieur: 0 cm; Longueur Chambranle intérieur: 0 cm; Superposition Chambranle intérieur: 0 cm; Épaisseur Intrados: 0 cm; Épaisseur Chambranle extérieur: 0 cm; Largeur Chambranle extérieur: 0 cm; Superposition Chambranle extérieur: 0 cm; Épaisseur Intrados extérieur: 0 cm; Décalage séparation intrados: 0 cm; IFC_Pset_Géométrie_CORNICHE depuis profil - Position: Aucune; sets with these values: 2; IFC_Pset_Géométrie_CORNICHE Extérieure à partir d'un profil - Décalage: 0; Angle: 0 deg; Symétrie: no; Fermer: no; sets with these values: 2; IFC_Pset_Géométrie_BASE Extérieure à partir d'un profil - Angle: 0 deg; Symétrie: no; Côté: 0 cm; sets with these values: 2; IFC_Pset_Géométrie - Côté extérieur: 0; Invertir (dte/gche): no; Invertir (intérieur/extérieur): no; Forme: Rectangle; Largeur: 110.087 cm; Hauteur: 246.98 cm; Hauteur 2: 0 cm; Rayon Arc: 0 cm; Rayon Cercle: 0 cm; Demi-axe horizontal: 0 cm; Demi-axe vertical: 0 cm; IFC_Pset_Géométrie_GRILLE - décalage: 0 cm; Offset latéral: 0 cm; Décalage supérieur: 0 cm; Décalage inférieur: 0 cm; Nombre accrochages latéraux: 0; Nombre d'accrochages supérieurs: 0; Nombre accrochages inférieurs: 0; IFC_Pset_Géométrie_Niche - Présent: no; Stratigraphie: Paroi en béton armé [120,00]; Épaisseur: 12 cm; Alignement: Intérieur; Décalage: 0 cm; IFC_Pset_Système de Référence Altimétrique_INFÉRIEUR - NIVEAU: Niveau 1 (Niveau 1 2343); delta: 46.6182 cm; sous Niveau: <aucun>; IFC_Pset_Données Métré - Surface de l'Ouverture: 27200 cm2; Surface de l'Ébrasement: 8900 cm2; Surface du Seuil: 0 cm2; Surface du Seuil intérieur: 0 cm2; Volume du seuil: 0 cm3; Volume du seuil intérieur: 0 cm3; Surface de la Niche: 0 cm2; Surface de la Grille: 0 cm2; Volume de la Grille: 0 cm3
Baie 442171 | Niveau 1 | 442171 | 114 | 9006 | 1 | -746779066 | Description: _VTO_Baie; CTLG_EXTERNAL_LINK - 1, DocType: 9; 1, Tag: 211; 1, Crc: -732809594; IFC_Pset_Caractéristiques - ID: 442171; Numérotation: 100; Numéro niveau: 04; Titre niveau: Niveau 1; IFC_Pset_Géométrie_Allège - Hauteur: 0 cm; Stratigraphie: ...; Épaisseur: 0 cm; IFC_Pset_Géométrie_Ébrasement - Présent: no; Côté supérieur: no; Côté INFÉRIEUR: no; Épaisseur extérieure: 0 cm; Épaisseur latérale gauche: 0 cm; Épaisseur latérale droite: 0 cm; Épiasseur latérale supérieure: 0 cm; Épaisseur diagonale gauche: 0 cm; Épaisseur diagonale droite: 0 cm; Épaisseur diagonale inférieure: 0 cm; Épaisseur diagonale supérieure: 0 cm; Épaisseur intérieur: 0 cm; IFC_Pset_Géométrie_Seuil - Type: Aucun; Épaisseur: 0 cm; Épaisseur interne: 0 cm; Décalage séparation: 0 cm; Appui extérieur: 0 cm; Appui intérieur: 0 cm; Côté latéral externe: 0 cm; Côté latéral interne: 0 cm; IFC_Pset_Géométrie_Chambranle - Position: Aucun; Épaisseur Chambranle intérieur: 0 cm; Longueur Chambranle intérieur: 0 cm; Superposition Chambranle intérieur: 0 cm; Épaisseur Intrados: 0 cm; Épaisseur Chambranle extérieur: 0 cm; Largeur Chambranle extérieur: 0 cm; Superposition Chambranle extérieur: 0 cm; Épaisseur Intrados extérieur: 0 cm; Décalage séparation intrados: 0 cm; IFC_Pset_Géométrie_CORNICHE depuis profil - Position: Aucune; sets with these values: 2; IFC_Pset_Géométrie_CORNICHE Extérieure à partir d'un profil - Décalage: 0; Angle: 0 deg; Symétrie: no; Fermer: no; sets with these values: 2; IFC_Pset_Géométrie_BASE Extérieure à partir d'un profil - Angle: 0 deg; Symétrie: no; Côté: 0 cm; sets with these values: 2; IFC_Pset_Géométrie - Côté extérieur: 1; Invertir (dte/gche): no; Invertir (intérieur/extérieur): no; Forme: Arc + Rectangle; Largeur: 159.184 cm; Hauteur: 41.2107 cm; Hauteur 2: 0 cm; Rayon Arc: 19.5453 cm; Rayon Cercle: 0 cm; Demi-axe horizontal: 0 cm; Demi-axe vertical: 0 cm; IFC_Pset_Géométrie_GRILLE - décalage: 0 cm; Offset latéral: 0 cm; Décalage supérieur: 0 cm; Décalage inférieur: 0 cm; Nombre accrochages latéraux: 0; Nombre d'accrochages supérieurs: 0; Nombre accrochages inférieurs: 0; IFC_Pset_Géométrie_Niche - Présent: no; Stratigraphie: Paroi en béton armé [120,00]; Épaisseur: 12 cm; Alignement: Intérieur; Décalage: 0 cm; IFC_Pset_Système de Référence Altimétrique_INFÉRIEUR - NIVEAU: Niveau 1 (Niveau 1 2343); delta: 285 cm; sous Niveau: <aucun>; IFC_Pset_Données Métré - Surface de l'Ouverture: 8600 cm2; Surface de l'Ébrasement: 0 cm2; Surface du Seuil: 0 cm2; Surface du Seuil intérieur: 0 cm2; Volume du seuil: 0 cm3; Volume du seuil intérieur: 0 cm3; Surface de la Niche: 0 cm2; Surface de la Grille: 0 cm2; Volume de la Grille: 0 cm3
Baie 442172 | Niveau 1 | 442172 | 114 | 9006 | 1 | -746779066 | Description: _VTO_Baie; CTLG_EXTERNAL_LINK - 1, DocType: 9; 1, Tag: 211; 1, Crc: -732809594; IFC_Pset_Caractéristiques - ID: 442172; Numérotation: 101; Numéro niveau: 04; Titre niveau: Niveau 1; IFC_Pset_Géométrie_Allège - Hauteur: 0 cm; Stratigraphie: ...; Épaisseur: 0 cm; IFC_Pset_Géométrie_Ébrasement - Présent: no; Côté supérieur: no; Côté INFÉRIEUR: no; Épaisseur extérieure: 0 cm; Épaisseur latérale gauche: 0 cm; Épaisseur latérale droite: 0 cm; Épiasseur latérale supérieure: 0 cm; Épaisseur diagonale gauche: 0 cm; Épaisseur diagonale droite: 0 cm; Épaisseur diagonale inférieure: 0 cm; Épaisseur diagonale supérieure: 0 cm; Épaisseur intérieur: 0 cm; IFC_Pset_Géométrie_Seuil - Type: Aucun; Épaisseur: 0 cm; Épaisseur interne: 0 cm; Décalage séparation: 0 cm; Appui extérieur: 0 cm; Appui intérieur: 0 cm; Côté latéral externe: 0 cm; Côté latéral interne: 0 cm; IFC_Pset_Géométrie_Chambranle - Position: Aucun; Épaisseur Chambranle intérieur: 0 cm; Longueur Chambranle intérieur: 0 cm; Superposition Chambranle intérieur: 0 cm; Épaisseur Intrados: 0 cm; Épaisseur Chambranle extérieur: 0 cm; Largeur Chambranle extérieur: 0 cm; Superposition Chambranle extérieur: 0 cm; Épaisseur Intrados extérieur: 0 cm; Décalage séparation intrados: 0 cm; IFC_Pset_Géométrie_CORNICHE depuis profil - Position: Aucune; sets with these values: 2; IFC_Pset_Géométrie_CORNICHE Extérieure à partir d'un profil - Décalage: 0; Angle: 0 deg; Symétrie: no; Fermer: no; sets with these values: 2; IFC_Pset_Géométrie_BASE Extérieure à partir d'un profil - Angle: 0 deg; Symétrie: no; Côté: 0 cm; sets with these values: 2; IFC_Pset_Géométrie - Côté extérieur: 0; Invertir (dte/gche): no; Invertir (intérieur/extérieur): no; Forme: Arc + Rectangle; Largeur: 159.356 cm; Hauteur: 41.2107 cm; Hauteur 2: 0 cm; Rayon Arc: 19.5665 cm; Rayon Cercle: 0 cm; Demi-axe horizontal: 0 cm; Demi-axe vertical: 0 cm; IFC_Pset_Géométrie_GRILLE - décalage: 0 cm; Offset latéral: 0 cm; Décalage supérieur: 0 cm; Décalage inférieur: 0 cm; Nombre accrochages latéraux: 0; Nombre d'accrochages supérieurs: 0; Nombre accrochages inférieurs: 0; IFC_Pset_Géométrie_Niche - Présent: no; Stratigraphie: Paroi en béton armé [120,00]; Épaisseur: 12 cm; Alignement: Intérieur; Décalage: 0 cm; IFC_Pset_Système de Référence Altimétrique_INFÉRIEUR - NIVEAU: Niveau 1 (Niveau 1 2343); delta: 285 cm; sous Niveau: <aucun>; IFC_Pset_Données Métré - Surface de l'Ouverture: 8700 cm2; Surface de l'Ébrasement: 0 cm2; Surface du Seuil: 0 cm2; Surface du Seuil intérieur: 0 cm2; Volume du seuil: 0 cm3; Volume du seuil intérieur: 0 cm3; Surface de la Niche: 0 cm2; Surface de la Grille: 0 cm2; Volume de la Grille: 0 cm3
Baie 442187 | Niveau 1 | 442187 | 114 | 9006 | 1 | -746779066 | Description: _VTO_Baie; CTLG_EXTERNAL_LINK - 1, DocType: 9; 1, Tag: 211; 1, Crc: -732809594; IFC_Pset_Caractéristiques - ID: 442187; Numérotation: 106; Numéro niveau: 04; Titre niveau: Niveau 1; IFC_Pset_Géométrie_Allège - Hauteur: 0 cm; Stratigraphie: ...; Épaisseur: 0 cm; IFC_Pset_Géométrie_Ébrasement - Présent: no; Côté supérieur: no; Côté INFÉRIEUR: no; Épaisseur extérieure: 0 cm; Épaisseur latérale gauche: 0 cm; Épaisseur latérale droite: 0 cm; Épiasseur latérale supérieure: 0 cm; Épaisseur diagonale gauche: 0 cm; Épaisseur diagonale droite: 0 cm; Épaisseur diagonale inférieure: 0 cm; Épaisseur diagonale supérieure: 0 cm; Épaisseur intérieur: 0 cm; IFC_Pset_Géométrie_Seuil - Type: Aucun; Épaisseur: 0 cm; Épaisseur interne: 0 cm; Décalage séparation: 0 cm; Appui extérieur: 0 cm; Appui intérieur: 0 cm; Côté latéral externe: 0 cm; Côté latéral interne: 0 cm; IFC_Pset_Géométrie_Chambranle - Position: Aucun; Épaisseur Chambranle intérieur: 0 cm; Longueur Chambranle intérieur: 0 cm; Superposition Chambranle intérieur: 0 cm; Épaisseur Intrados: 0 cm; Épaisseur Chambranle extérieur: 0 cm; Largeur Chambranle extérieur: 0 cm; Superposition Chambranle extérieur: 0 cm; Épaisseur Intrados extérieur: 0 cm; Décalage séparation intrados: 0 cm; IFC_Pset_Géométrie_CORNICHE depuis profil - Position: Aucune; sets with these values: 2; IFC_Pset_Géométrie_CORNICHE Extérieure à partir d'un profil - Décalage: 0; Angle: 0 deg; Symétrie: no; Fermer: no; sets with these values: 2; IFC_Pset_Géométrie_BASE Extérieure à partir d'un profil - Angle: 0 deg; Symétrie: no; Côté: 0 cm; sets with these values: 2; IFC_Pset_Géométrie - Côté extérieur: 0; Invertir (dte/gche): no; Invertir (intérieur/extérieur): no; Forme: Rectangle; Largeur: 111.475 cm; Hauteur: 240 cm; Hauteur 2: 0 cm; Rayon Arc: 0 cm; Rayon Cercle: 0 cm; Demi-axe horizontal: 0 cm; Demi-axe vertical: 0 cm; IFC_Pset_Géométrie_GRILLE - décalage: 0 cm; Offset latéral: 0 cm; Décalage supérieur: 0 cm; Décalage inférieur: 0 cm; Nombre accrochages latéraux: 0; Nombre d'accrochages supérieurs: 0; Nombre accrochages inférieurs: 0; IFC_Pset_Géométrie_Niche - Présent: no; Stratigraphie: Paroi en béton armé [120,00]; Épaisseur: 12 cm; Alignement: Intérieur; Décalage: 0 cm; IFC_Pset_Système de Référence Altimétrique_INFÉRIEUR - NIVEAU: Niveau 1 (Niveau 1 2343); delta: 0.0128504 cm; sous Niveau: <aucun>; IFC_Pset_Données Métré - Surface de l'Ouverture: 26800 cm2; Surface de l'Ébrasement: 0 cm2; Surface du Seuil: 0 cm2; Surface du Seuil intérieur: 0 cm2; Volume du seuil: 0 cm3; Volume du seuil intérieur: 0 cm3; Surface de la Niche: 0 cm2; Surface de la Grille: 0 cm2; Volume de la Grille: 0 cm3
Baie 442186 | Niveau 1 | 442186 | 114 | 9006 | 1 | -746779066 | Description: _VTO_Baie; CTLG_EXTERNAL_LINK - 1, DocType: 9; 1, Tag: 211; 1, Crc: -732809594; IFC_Pset_Caractéristiques - ID: 442186; Numérotation: 105; Numéro niveau: 04; Titre niveau: Niveau 1; IFC_Pset_Géométrie_Allège - Hauteur: 0 cm; Stratigraphie: ...; Épaisseur: 0 cm; IFC_Pset_Géométrie_Ébrasement - Présent: no; Côté supérieur: no; Côté INFÉRIEUR: no; Épaisseur extérieure: 0 cm; Épaisseur latérale gauche: 0 cm; Épaisseur latérale droite: 0 cm; Épiasseur latérale supérieure: 0 cm; Épaisseur diagonale gauche: 0 cm; Épaisseur diagonale droite: 0 cm; Épaisseur diagonale inférieure: 0 cm; Épaisseur diagonale supérieure: 0 cm; Épaisseur intérieur: 0 cm; IFC_Pset_Géométrie_Seuil - Type: Aucun; Épaisseur: 0 cm; Épaisseur interne: 0 cm; Décalage séparation: 0 cm; Appui extérieur: 0 cm; Appui intérieur: 0 cm; Côté latéral externe: 0 cm; Côté latéral interne: 0 cm; IFC_Pset_Géométrie_Chambranle - Position: Aucun; Épaisseur Chambranle intérieur: 0 cm; Longueur Chambranle intérieur: 0 cm; Superposition Chambranle intérieur: 0 cm; Épaisseur Intrados: 0 cm; Épaisseur Chambranle extérieur: 0 cm; Largeur Chambranle extérieur: 0 cm; Superposition Chambranle extérieur: 0 cm; Épaisseur Intrados extérieur: 0 cm; Décalage séparation intrados: 0 cm; IFC_Pset_Géométrie_CORNICHE depuis profil - Position: Aucune; sets with these values: 2; IFC_Pset_Géométrie_CORNICHE Extérieure à partir d'un profil - Décalage: 0; Angle: 0 deg; Symétrie: no; Fermer: no; sets with these values: 2; IFC_Pset_Géométrie_BASE Extérieure à partir d'un profil - Angle: 0 deg; Symétrie: no; Côté: 0 cm; sets with these values: 2; IFC_Pset_Géométrie - Côté extérieur: 1; Invertir (dte/gche): no; Invertir (intérieur/extérieur): yes; Forme: Rectangle; Largeur: 111.08 cm; Hauteur: 291.3 cm; Hauteur 2: 0 cm; Rayon Arc: 0 cm; Rayon Cercle: 0 cm; Demi-axe horizontal: 0 cm; Demi-axe vertical: 0 cm; IFC_Pset_Géométrie_GRILLE - décalage: 0 cm; Offset latéral: 0 cm; Décalage supérieur: 0 cm; Décalage inférieur: 0 cm; Nombre accrochages latéraux: 0; Nombre d'accrochages supérieurs: 0; Nombre accrochages inférieurs: 0; IFC_Pset_Géométrie_Niche - Présent: no; Stratigraphie: Paroi en béton armé [120,00]; Épaisseur: 12 cm; Alignement: Intérieur; Décalage: 0 cm; IFC_Pset_Système de Référence Altimétrique_INFÉRIEUR - NIVEAU: Niveau 1 (Niveau 1 2343); delta: 0.0128504 cm; sous Niveau: <aucun>; IFC_Pset_Données Métré - Surface de l'Ouverture: 32400 cm2; Surface de l'Ébrasement: 0 cm2; Surface du Seuil: 0 cm2; Surface du Seuil intérieur: 0 cm2; Volume du seuil: 0 cm3; Volume du seuil intérieur: 0 cm3; Surface de la Niche: 0 cm2; Surface de la Grille: 0 cm2; Volume de la Grille: 0 cm3
Baie 442299 | Niveau 1 | 442299 | 114 | 9006 | 1 | -746779066 | Description: _VTO_Baie; CTLG_EXTERNAL_LINK - 1, DocType: 9; 1, Tag: 211; 1, Crc: -732809594; IFC_Pset_Caractéristiques - ID: 442299; Numérotation: 109; Numéro niveau: 04; Titre niveau: Niveau 1; IFC_Pset_Géométrie_Allège - Hauteur: 0 cm; Stratigraphie: ...; Épaisseur: 0 cm; IFC_Pset_Géométrie_Ébrasement - Présent: yes; Côté supérieur: no; Côté INFÉRIEUR: no; Épaisseur extérieure: 11 cm; Épaisseur latérale gauche: 3 cm; Épaisseur latérale droite: 3 cm; Épiasseur latérale supérieure: 3 cm; Épaisseur diagonale gauche: 0 cm; Épaisseur diagonale droite: 0 cm; Épaisseur diagonale inférieure: 0 cm; Épaisseur diagonale supérieure: 0 cm; Épaisseur intérieur: 0 cm; Données: [a : 110,00; b: 30,00; c: 0,00; d: 0,00] mm; IFC_Pset_Géométrie_Seuil - Type: Aucun; Épaisseur: 0 cm; Épaisseur interne: 0 cm; Décalage séparation: 0 cm; Appui extérieur: 0 cm; Appui intérieur: 0 cm; Côté latéral externe: 0 cm; Côté latéral interne: 0 cm; IFC_Pset_Géométrie_Chambranle - Position: Aucun; Épaisseur Chambranle intérieur: 0 cm; Longueur Chambranle intérieur: 0 cm; Superposition Chambranle intérieur: 0 cm; Épaisseur Intrados: 0 cm; Épaisseur Chambranle extérieur: 0 cm; Largeur Chambranle extérieur: 0 cm; Superposition Chambranle extérieur: 0 cm; Épaisseur Intrados extérieur: 0 cm; Décalage séparation intrados: 0 cm; IFC_Pset_Géométrie_CORNICHE depuis profil - Position: Aucune; sets with these values: 2; IFC_Pset_Géométrie_CORNICHE Extérieure à partir d'un profil - Décalage: 0; Angle: 0 deg; Symétrie: no; Fermer: no; sets with these values: 2; IFC_Pset_Géométrie_BASE Extérieure à partir d'un profil - Angle: 0 deg; Symétrie: no; Côté: 0 cm; sets with these values: 2; IFC_Pset_Géométrie - Côté extérieur: 0; Invertir (dte/gche): no; Invertir (intérieur/extérieur): no; Forme: Rectangle; Largeur: 109.985 cm; Hauteur: 294.389 cm; Hauteur 2: 0 cm; Rayon Arc: 0 cm; Rayon Cercle: 0 cm; Demi-axe horizontal: 0 cm; Demi-axe vertical: 0 cm; IFC_Pset_Géométrie_GRILLE - décalage: 0 cm; Offset latéral: 0 cm; Décalage supérieur: 0 cm; Décalage inférieur: 0 cm; Nombre accrochages latéraux: 0; Nombre d'accrochages supérieurs: 0; Nombre accrochages inférieurs: 0; IFC_Pset_Géométrie_Niche - Présent: no; Stratigraphie: Paroi en béton armé [120,00]; Épaisseur: 12 cm; Alignement: Intérieur; Décalage: 0 cm; IFC_Pset_Système de Référence Altimétrique_INFÉRIEUR - NIVEAU: Niveau 1 (Niveau 1 2343); delta: 0.0128504 cm; sous Niveau: <aucun>; IFC_Pset_Données Métré - Surface de l'Ouverture: 32400 cm2; Surface de l'Ébrasement: 10600 cm2; Surface du Seuil: 0 cm2; Surface du Seuil intérieur: 0 cm2; Volume du seuil: 0 cm3; Volume du seuil intérieur: 0 cm3; Surface de la Niche: 0 cm2; Surface de la Grille: 0 cm2; Volume de la Grille: 0 cm3
Baie 442298 | Niveau 1 | 442298 | 114 | 9006 | 1 | -746779066 | Description: _VTO_Baie; CTLG_EXTERNAL_LINK - 1, DocType: 9; 1, Tag: 211; 1, Crc: -732809594; IFC_Pset_Caractéristiques - ID: 442298; Numérotation: 108; Numéro niveau: 04; Titre niveau: Niveau 1; IFC_Pset_Géométrie_Allège - Hauteur: 0 cm; Stratigraphie: ...; Épaisseur: 0 cm; IFC_Pset_Géométrie_Ébrasement - Présent: yes; Côté supérieur: no; Côté INFÉRIEUR: no; Épaisseur extérieure: 11 cm; Épaisseur latérale gauche: 3 cm; Épaisseur latérale droite: 3 cm; Épiasseur latérale supérieure: 3 cm; Épaisseur diagonale gauche: 0 cm; Épaisseur diagonale droite: 0 cm; Épaisseur diagonale inférieure: 0 cm; Épaisseur diagonale supérieure: 0 cm; Épaisseur intérieur: 0 cm; Données: [a : 110,00; b: 30,00; c: 0,00; d: 0,00] mm; IFC_Pset_Géométrie_Seuil - Type: Aucun; Épaisseur: 0 cm; Épaisseur interne: 0 cm; Décalage séparation: 0 cm; Appui extérieur: 0 cm; Appui intérieur: 0 cm; Côté latéral externe: 0 cm; Côté latéral interne: 0 cm; IFC_Pset_Géométrie_Chambranle - Position: Aucun; Épaisseur Chambranle intérieur: 0 cm; Longueur Chambranle intérieur: 0 cm; Superposition Chambranle intérieur: 0 cm; Épaisseur Intrados: 0 cm; Épaisseur Chambranle extérieur: 0 cm; Largeur Chambranle extérieur: 0 cm; Superposition Chambranle extérieur: 0 cm; Épaisseur Intrados extérieur: 0 cm; Décalage séparation intrados: 0 cm; IFC_Pset_Géométrie_CORNICHE depuis profil - Position: Aucune; sets with these values: 2; IFC_Pset_Géométrie_CORNICHE Extérieure à partir d'un profil - Décalage: 0; Angle: 0 deg; Symétrie: no; Fermer: no; sets with these values: 2; IFC_Pset_Géométrie_BASE Extérieure à partir d'un profil - Angle: 0 deg; Symétrie: no; Côté: 0 cm; sets with these values: 2; IFC_Pset_Géométrie - Côté extérieur: 0; Invertir (dte/gche): no; Invertir (intérieur/extérieur): no; Forme: Rectangle; Largeur: 109.985 cm; Hauteur: 294.085 cm; Hauteur 2: 0 cm; Rayon Arc: 0 cm; Rayon Cercle: 0 cm; Demi-axe horizontal: 0 cm; Demi-axe vertical: 0 cm; IFC_Pset_Géométrie_GRILLE - décalage: 0 cm; Offset latéral: 0 cm; Décalage supérieur: 0 cm; Décalage inférieur: 0 cm; Nombre accrochages latéraux: 0; Nombre d'accrochages supérieurs: 0; Nombre accrochages inférieurs: 0; IFC_Pset_Géométrie_Niche - Présent: no; Stratigraphie: Paroi en béton armé [120,00]; Épaisseur: 12 cm; Alignement: Intérieur; Décalage: 0 cm; IFC_Pset_Système de Référence Altimétrique_INFÉRIEUR - NIVEAU: Niveau 1 (Niveau 1 2343); delta: 0.0128504 cm; sous Niveau: <aucun>; IFC_Pset_Données Métré - Surface de l'Ouverture: 32300 cm2; Surface de l'Ébrasement: 10600 cm2; Surface du Seuil: 0 cm2; Surface du Seuil intérieur: 0 cm2; Volume du seuil: 0 cm3; Volume du seuil intérieur: 0 cm3; Surface de la Niche: 0 cm2; Surface de la Grille: 0 cm2; Volume de la Grille: 0 cm3
Baie 426929 | Niveau 1 | 426929 | 114 | 9006 | 1 | -746779066 | Description: _VTO_Baie; CTLG_EXTERNAL_LINK - 1, DocType: 9; 1, Tag: 211; 1, Crc: -732809594; IFC_Pset_Caractéristiques - ID: 426929; Numérotation: 087; Numéro niveau: 04; Titre niveau: Niveau 1; IFC_Pset_Géométrie_Allège - Hauteur: 0 cm; Stratigraphie: ...; Épaisseur: 0 cm; IFC_Pset_Géométrie_Ébrasement - Présent: yes; Côté supérieur: no; Côté INFÉRIEUR: no; Épaisseur extérieure: 11 cm; Épaisseur latérale gauche: 3 cm; Épaisseur latérale droite: 3 cm; Épiasseur latérale supérieure: 3 cm; Épaisseur diagonale gauche: 0 cm; Épaisseur diagonale droite: 0 cm; Épaisseur diagonale inférieure: 0 cm; Épaisseur diagonale supérieure: 0 cm; Épaisseur intérieur: 0 cm; Données: [a : 110,00; b: 30,00; c: 0,00; d: 0,00] mm; IFC_Pset_Géométrie_Seuil - Type: Aucun; Épaisseur: 0 cm; Épaisseur interne: 0 cm; Décalage séparation: 0 cm; Appui extérieur: 0 cm; Appui intérieur: 0 cm; Côté latéral externe: 0 cm; Côté latéral interne: 0 cm; IFC_Pset_Géométrie_Chambranle - Position: Aucun; Épaisseur Chambranle intérieur: 0 cm; Longueur Chambranle intérieur: 0 cm; Superposition Chambranle intérieur: 0 cm; Épaisseur Intrados: 0 cm; Épaisseur Chambranle extérieur: 0 cm; Largeur Chambranle extérieur: 0 cm; Superposition Chambranle extérieur: 0 cm; Épaisseur Intrados extérieur: 0 cm; Décalage séparation intrados: 0 cm; IFC_Pset_Géométrie_CORNICHE depuis profil - Position: Aucune; sets with these values: 2; IFC_Pset_Géométrie_CORNICHE Extérieure à partir d'un profil - Décalage: 0; Angle: 0 deg; Symétrie: no; Fermer: no; sets with these values: 2; IFC_Pset_Géométrie_BASE Extérieure à partir d'un profil - Angle: 0 deg; Symétrie: no; Côté: 0 cm; sets with these values: 2; IFC_Pset_Géométrie - Côté extérieur: 0; Invertir (dte/gche): no; Invertir (intérieur/extérieur): no; Forme: Rectangle; Largeur: 109.719 cm; Hauteur: 246.833 cm; Hauteur 2: 0 cm; Rayon Arc: 0 cm; Rayon Cercle: 0 cm; Demi-axe horizontal: 0 cm; Demi-axe vertical: 0 cm; IFC_Pset_Géométrie_GRILLE - décalage: 0 cm; Offset latéral: 0 cm; Décalage supérieur: 0 cm; Décalage inférieur: 0 cm; Nombre accrochages latéraux: 0; Nombre d'accrochages supérieurs: 0; Nombre accrochages inférieurs: 0; IFC_Pset_Géométrie_Niche - Présent: no; Stratigraphie: Paroi en béton armé [120,00]; Épaisseur: 12 cm; Alignement: Intérieur; Décalage: 0 cm; IFC_Pset_Système de Référence Altimétrique_INFÉRIEUR - NIVEAU: Niveau 1 (Niveau 1 2343); delta: 45.7998 cm; sous Niveau: <aucun>; IFC_Pset_Données Métré - Surface de l'Ouverture: 27100 cm2; Surface de l'Ébrasement: 8900 cm2; Surface du Seuil: 0 cm2; Surface du Seuil intérieur: 0 cm2; Volume du seuil: 0 cm3; Volume du seuil intérieur: 0 cm3; Surface de la Niche: 0 cm2; Surface de la Grille: 0 cm2; Volume de la Grille: 0 cm3
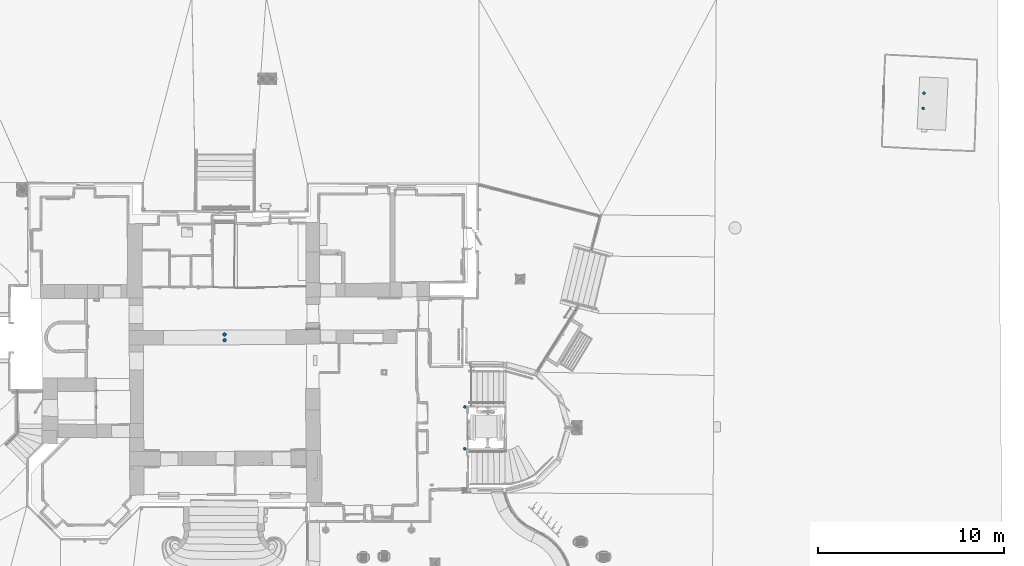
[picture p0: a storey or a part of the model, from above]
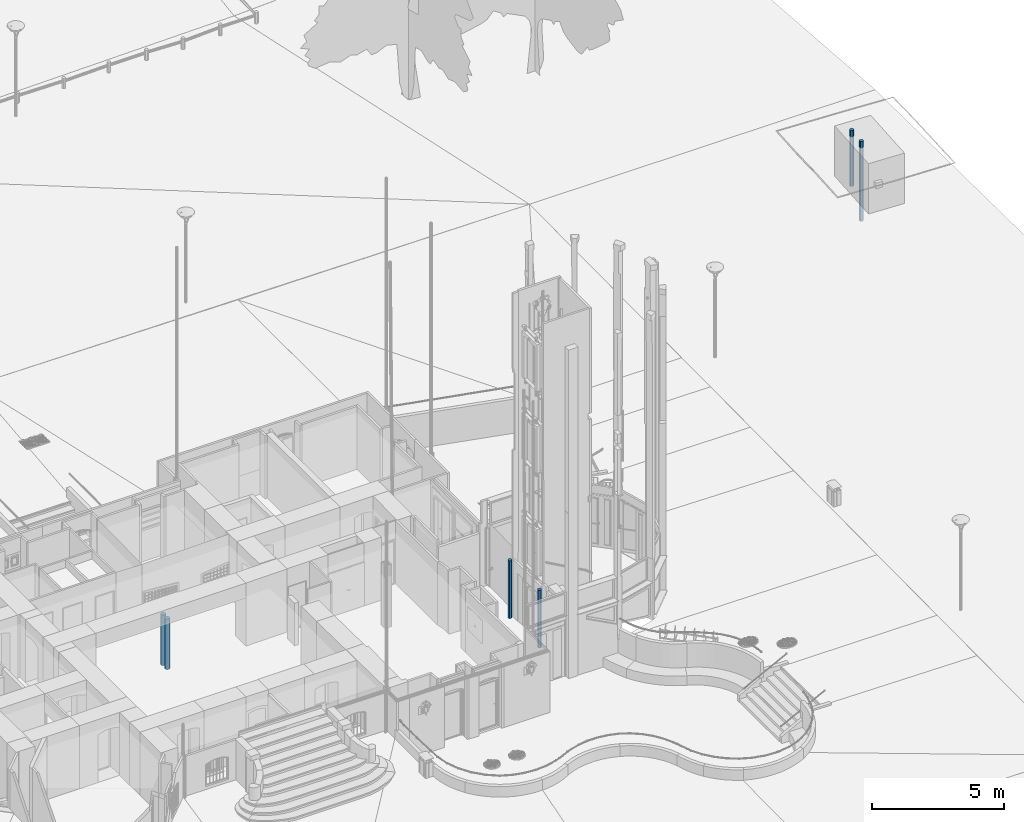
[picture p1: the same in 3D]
Properties of the parts of a building model (IFC2X3), part 14 of 37

# IfcOpeningElement: Opening (367)
Name | In | __RECOGNIZE__, ID | TPLG | TPLG_OD | GENERATE | 0, Crc
Baie 426928 | Niveau 1 | 426928 | 114 | 9006 | 1 | -746779066 | Description: _VTO_Baie; CTLG_EXTERNAL_LINK - 1, DocType: 9; 1, Tag: 211; 1, Crc: -732809594; IFC_Pset_Caractéristiques - ID: 426928; Numérotation: 086; Numéro niveau: 04; Titre niveau: Niveau 1; IFC_Pset_Géométrie_Allège - Hauteur: 0 cm; Stratigraphie: ...; Épaisseur: 0 cm; IFC_Pset_Géométrie_Ébrasement - Présent: yes; Côté supérieur: no; Côté INFÉRIEUR: no; Épaisseur extérieure: 11 cm; Épaisseur latérale gauche: 3 cm; Épaisseur latérale droite: 3 cm; Épiasseur latérale supérieure: 3 cm; Épaisseur diagonale gauche: 0 cm; Épaisseur diagonale droite: 0 cm; Épaisseur diagonale inférieure: 0 cm; Épaisseur diagonale supérieure: 0 cm; Épaisseur intérieur: 0 cm; Données: [a : 110,00; b: 30,00; c: 0,00; d: 0,00] mm; IFC_Pset_Géométrie_Seuil - Type: Aucun; Épaisseur: 0 cm; Épaisseur interne: 0 cm; Décalage séparation: 0 cm; Appui extérieur: 0 cm; Appui intérieur: 0 cm; Côté latéral externe: 0 cm; Côté latéral interne: 0 cm; IFC_Pset_Géométrie_Chambranle - Position: Aucun; Épaisseur Chambranle intérieur: 0 cm; Longueur Chambranle intérieur: 0 cm; Superposition Chambranle intérieur: 0 cm; Épaisseur Intrados: 0 cm; Épaisseur Chambranle extérieur: 0 cm; Largeur Chambranle extérieur: 0 cm; Superposition Chambranle extérieur: 0 cm; Épaisseur Intrados extérieur: 0 cm; Décalage séparation intrados: 0 cm; IFC_Pset_Géométrie_CORNICHE depuis profil - Position: Aucune; sets with these values: 2; IFC_Pset_Géométrie_CORNICHE Extérieure à partir d'un profil - Décalage: 0; Angle: 0 deg; Symétrie: no; Fermer: no; sets with these values: 2; IFC_Pset_Géométrie_BASE Extérieure à partir d'un profil - Angle: 0 deg; Symétrie: no; Côté: 0 cm; sets with these values: 2; IFC_Pset_Géométrie - Côté extérieur: 0; Invertir (dte/gche): no; Invertir (intérieur/extérieur): no; Forme: Rectangle; Largeur: 110.709 cm; Hauteur: 246.833 cm; Hauteur 2: 0 cm; Rayon Arc: 0 cm; Rayon Cercle: 0 cm; Demi-axe horizontal: 0 cm; Demi-axe vertical: 0 cm; IFC_Pset_Géométrie_GRILLE - décalage: 0 cm; Offset latéral: 0 cm; Décalage supérieur: 0 cm; Décalage inférieur: 0 cm; Nombre accrochages latéraux: 0; Nombre d'accrochages supérieurs: 0; Nombre accrochages inférieurs: 0; IFC_Pset_Géométrie_Niche - Présent: no; Stratigraphie: Paroi en béton armé [120,00]; Épaisseur: 12 cm; Alignement: Intérieur; Décalage: 0 cm; IFC_Pset_Système de Référence Altimétrique_INFÉRIEUR - NIVEAU: Niveau 1 (Niveau 1 2343); delta: 45.9432 cm; sous Niveau: <aucun>; IFC_Pset_Données Métré - Surface de l'Ouverture: 27300 cm2; Surface de l'Ébrasement: 8900 cm2; Surface du Seuil: 0 cm2; Surface du Seuil intérieur: 0 cm2; Volume du seuil: 0 cm3; Volume du seuil intérieur: 0 cm3; Surface de la Niche: 0 cm2; Surface de la Grille: 0 cm2; Volume de la Grille: 0 cm3
Baie 426956 | Niveau 1 | 426956 | 114 | 9006 | 1 | -746779066 | Description: _VTO_Baie; CTLG_EXTERNAL_LINK - 1, DocType: 9; 1, Tag: 211; 1, Crc: -732809594; IFC_Pset_Caractéristiques - ID: 426956; Numérotation: 089; Numéro niveau: 04; Titre niveau: Niveau 1; IFC_Pset_Géométrie_Allège - Hauteur: 0 cm; Stratigraphie: ...; Épaisseur: 0 cm; IFC_Pset_Géométrie_Ébrasement - Présent: yes; Côté supérieur: no; Côté INFÉRIEUR: no; Épaisseur extérieure: 11 cm; Épaisseur latérale gauche: 3 cm; Épaisseur latérale droite: 3 cm; Épiasseur latérale supérieure: 3 cm; Épaisseur diagonale gauche: 0 cm; Épaisseur diagonale droite: 0 cm; Épaisseur diagonale inférieure: 0 cm; Épaisseur diagonale supérieure: 0 cm; Épaisseur intérieur: 0 cm; Données: [a : 110,00; b: 30,00; c: 0,00; d: 0,00] mm; IFC_Pset_Géométrie_Seuil - Type: Aucun; Épaisseur: 0 cm; Épaisseur interne: 0 cm; Décalage séparation: 0 cm; Appui extérieur: 0 cm; Appui intérieur: 0 cm; Côté latéral externe: 0 cm; Côté latéral interne: 0 cm; IFC_Pset_Géométrie_Chambranle - Position: Aucun; Épaisseur Chambranle intérieur: 0 cm; Longueur Chambranle intérieur: 0 cm; Superposition Chambranle intérieur: 0 cm; Épaisseur Intrados: 0 cm; Épaisseur Chambranle extérieur: 0 cm; Largeur Chambranle extérieur: 0 cm; Superposition Chambranle extérieur: 0 cm; Épaisseur Intrados extérieur: 0 cm; Décalage séparation intrados: 0 cm; IFC_Pset_Géométrie_CORNICHE depuis profil - Position: Aucune; sets with these values: 2; IFC_Pset_Géométrie_CORNICHE Extérieure à partir d'un profil - Décalage: 0; Angle: 0 deg; Symétrie: no; Fermer: no; sets with these values: 2; IFC_Pset_Géométrie_BASE Extérieure à partir d'un profil - Angle: 0 deg; Symétrie: no; Côté: 0 cm; sets with these values: 2; IFC_Pset_Géométrie - Côté extérieur: 0; Invertir (dte/gche): no; Invertir (intérieur/extérieur): no; Forme: Rectangle; Largeur: 69.6974 cm; Hauteur: 248.666 cm; Hauteur 2: 0 cm; Rayon Arc: 0 cm; Rayon Cercle: 0 cm; Demi-axe horizontal: 0 cm; Demi-axe vertical: 0 cm; IFC_Pset_Géométrie_GRILLE - décalage: 0 cm; Offset latéral: 0 cm; Décalage supérieur: 0 cm; Décalage inférieur: 0 cm; Nombre accrochages latéraux: 0; Nombre d'accrochages supérieurs: 0; Nombre accrochages inférieurs: 0; IFC_Pset_Géométrie_Niche - Présent: no; Stratigraphie: Paroi en béton armé [120,00]; Épaisseur: 12 cm; Alignement: Intérieur; Décalage: 0 cm; IFC_Pset_Système de Référence Altimétrique_INFÉRIEUR - NIVEAU: Niveau 1 (Niveau 1 2343); delta: 46.2969 cm; sous Niveau: <aucun>; IFC_Pset_Données Métré - Surface de l'Ouverture: 17300 cm2; Surface de l'Ébrasement: 9000 cm2; Surface du Seuil: 0 cm2; Surface du Seuil intérieur: 0 cm2; Volume du seuil: 0 cm3; Volume du seuil intérieur: 0 cm3; Surface de la Niche: 0 cm2; Surface de la Grille: 0 cm2; Volume de la Grille: 0 cm3
Baie 426955 | Niveau 1 | 426955 | 114 | 9006 | 1 | -746779066 | Description: _VTO_Baie; CTLG_EXTERNAL_LINK - 1, DocType: 9; 1, Tag: 211; 1, Crc: -732809594; IFC_Pset_Caractéristiques - ID: 426955; Numérotation: 088; Numéro niveau: 04; Titre niveau: Niveau 1; IFC_Pset_Géométrie_Allège - Hauteur: 0 cm; Stratigraphie: ...; Épaisseur: 0 cm; IFC_Pset_Géométrie_Ébrasement - Présent: yes; Côté supérieur: no; Côté INFÉRIEUR: no; Épaisseur extérieure: 11 cm; Épaisseur latérale gauche: 3 cm; Épaisseur latérale droite: 3 cm; Épiasseur latérale supérieure: 3 cm; Épaisseur diagonale gauche: 0 cm; Épaisseur diagonale droite: 0 cm; Épaisseur diagonale inférieure: 0 cm; Épaisseur diagonale supérieure: 0 cm; Épaisseur intérieur: 0 cm; Données: [a : 110,00; b: 30,00; c: 0,00; d: 0,00] mm; IFC_Pset_Géométrie_Seuil - Type: Aucun; Épaisseur: 0 cm; Épaisseur interne: 0 cm; Décalage séparation: 0 cm; Appui extérieur: 0 cm; Appui intérieur: 0 cm; Côté latéral externe: 0 cm; Côté latéral interne: 0 cm; IFC_Pset_Géométrie_Chambranle - Position: Aucun; Épaisseur Chambranle intérieur: 0 cm; Longueur Chambranle intérieur: 0 cm; Superposition Chambranle intérieur: 0 cm; Épaisseur Intrados: 0 cm; Épaisseur Chambranle extérieur: 0 cm; Largeur Chambranle extérieur: 0 cm; Superposition Chambranle extérieur: 0 cm; Épaisseur Intrados extérieur: 0 cm; Décalage séparation intrados: 0 cm; IFC_Pset_Géométrie_CORNICHE depuis profil - Position: Aucune; sets with these values: 2; IFC_Pset_Géométrie_CORNICHE Extérieure à partir d'un profil - Décalage: 0; Angle: 0 deg; Symétrie: no; Fermer: no; sets with these values: 2; IFC_Pset_Géométrie_BASE Extérieure à partir d'un profil - Angle: 0 deg; Symétrie: no; Côté: 0 cm; sets with these values: 2; IFC_Pset_Géométrie - Côté extérieur: 0; Invertir (dte/gche): no; Invertir (intérieur/extérieur): no; Forme: Rectangle; Largeur: 69.6727 cm; Hauteur: 248.7 cm; Hauteur 2: 0 cm; Rayon Arc: 0 cm; Rayon Cercle: 0 cm; Demi-axe horizontal: 0 cm; Demi-axe vertical: 0 cm; IFC_Pset_Géométrie_GRILLE - décalage: 0 cm; Offset latéral: 0 cm; Décalage supérieur: 0 cm; Décalage inférieur: 0 cm; Nombre accrochages latéraux: 0; Nombre d'accrochages supérieurs: 0; Nombre accrochages inférieurs: 0; IFC_Pset_Géométrie_Niche - Présent: no; Stratigraphie: Paroi en béton armé [120,00]; Épaisseur: 12 cm; Alignement: Intérieur; Décalage: 0 cm; IFC_Pset_Système de Référence Altimétrique_INFÉRIEUR - NIVEAU: Niveau 1 (Niveau 1 2343); delta: 46.3 cm; sous Niveau: <aucun>; IFC_Pset_Données Métré - Surface de l'Ouverture: 17300 cm2; Surface de l'Ébrasement: 9000 cm2; Surface du Seuil: 0 cm2; Surface du Seuil intérieur: 0 cm2; Volume du seuil: 0 cm3; Volume du seuil intérieur: 0 cm3; Surface de la Niche: 0 cm2; Surface de la Grille: 0 cm2; Volume de la Grille: 0 cm3
Baie 426927 | Niveau 1 | 426927 | 114 | 9006 | 1 | -746779066 | Description: _VTO_Baie; CTLG_EXTERNAL_LINK - 1, DocType: 9; 1, Tag: 211; 1, Crc: -732809594; IFC_Pset_Caractéristiques - ID: 426927; Numérotation: 085; Numéro niveau: 04; Titre niveau: Niveau 1; IFC_Pset_Géométrie_Allège - Hauteur: 0 cm; Stratigraphie: ...; Épaisseur: 0 cm; IFC_Pset_Géométrie_Ébrasement - Présent: yes; Côté supérieur: no; Côté INFÉRIEUR: no; Épaisseur extérieure: 11 cm; Épaisseur latérale gauche: 3 cm; Épaisseur latérale droite: 3 cm; Épiasseur latérale supérieure: 3 cm; Épaisseur diagonale gauche: 0 cm; Épaisseur diagonale droite: 0 cm; Épaisseur diagonale inférieure: 0 cm; Épaisseur diagonale supérieure: 0 cm; Épaisseur intérieur: 0 cm; Données: [a : 110,00; b: 30,00; c: 0,00; d: 0,00] mm; IFC_Pset_Géométrie_Seuil - Type: Aucun; Épaisseur: 0 cm; Épaisseur interne: 0 cm; Décalage séparation: 0 cm; Appui extérieur: 0 cm; Appui intérieur: 0 cm; Côté latéral externe: 0 cm; Côté latéral interne: 0 cm; IFC_Pset_Géométrie_Chambranle - Position: Aucun; Épaisseur Chambranle intérieur: 0 cm; Longueur Chambranle intérieur: 0 cm; Superposition Chambranle intérieur: 0 cm; Épaisseur Intrados: 0 cm; Épaisseur Chambranle extérieur: 0 cm; Largeur Chambranle extérieur: 0 cm; Superposition Chambranle extérieur: 0 cm; Épaisseur Intrados extérieur: 0 cm; Décalage séparation intrados: 0 cm; IFC_Pset_Géométrie_CORNICHE depuis profil - Position: Aucune; sets with these values: 2; IFC_Pset_Géométrie_CORNICHE Extérieure à partir d'un profil - Décalage: 0; Angle: 0 deg; Symétrie: no; Fermer: no; sets with these values: 2; IFC_Pset_Géométrie_BASE Extérieure à partir d'un profil - Angle: 0 deg; Symétrie: no; Côté: 0 cm; sets with these values: 2; IFC_Pset_Géométrie - Côté extérieur: 0; Invertir (dte/gche): no; Invertir (intérieur/extérieur): no; Forme: Rectangle; Largeur: 109.889 cm; Hauteur: 243 cm; Hauteur 2: 0 cm; Rayon Arc: 0 cm; Rayon Cercle: 0 cm; Demi-axe horizontal: 0 cm; Demi-axe vertical: 0 cm; IFC_Pset_Géométrie_GRILLE - décalage: 0 cm; Offset latéral: 0 cm; Décalage supérieur: 0 cm; Décalage inférieur: 0 cm; Nombre accrochages latéraux: 0; Nombre d'accrochages supérieurs: 0; Nombre accrochages inférieurs: 0; IFC_Pset_Géométrie_Niche - Présent: no; Stratigraphie: Paroi en béton armé [120,00]; Épaisseur: 12 cm; Alignement: Intérieur; Décalage: 0 cm; IFC_Pset_Système de Référence Altimétrique_INFÉRIEUR - NIVEAU: Niveau 1 (Niveau 1 2343); delta: 50.4217 cm; sous Niveau: <aucun>; IFC_Pset_Données Métré - Surface de l'Ouverture: 26700 cm2; Surface de l'Ébrasement: 8700 cm2; Surface du Seuil: 0 cm2; Surface du Seuil intérieur: 0 cm2; Volume du seuil: 0 cm3; Volume du seuil intérieur: 0 cm3; Surface de la Niche: 0 cm2; Surface de la Grille: 0 cm2; Volume de la Grille: 0 cm3
Baie 442676 | Niveau 1 | 442676 | 114 | 9006 | 1 | -746779066 | Description: _VTO_Baie; CTLG_EXTERNAL_LINK - 1, DocType: 9; 1, Tag: 211; 1, Crc: -732809594; IFC_Pset_Caractéristiques - ID: 442676; Numérotation: 111; Numéro niveau: 04; Titre niveau: Niveau 1; IFC_Pset_Géométrie_Allège - Hauteur: 0 cm; Stratigraphie: ...; Épaisseur: 0 cm; IFC_Pset_Géométrie_Ébrasement - Présent: no; Côté supérieur: no; Côté INFÉRIEUR: no; Épaisseur extérieure: 0 cm; Épaisseur latérale gauche: 0 cm; Épaisseur latérale droite: 0 cm; Épiasseur latérale supérieure: 0 cm; Épaisseur diagonale gauche: 0 cm; Épaisseur diagonale droite: 0 cm; Épaisseur diagonale inférieure: 0 cm; Épaisseur diagonale supérieure: 0 cm; Épaisseur intérieur: 0 cm; IFC_Pset_Géométrie_Seuil - Type: Aucun; Épaisseur: 0 cm; Épaisseur interne: 0 cm; Décalage séparation: 0 cm; Appui extérieur: 0 cm; Appui intérieur: 0 cm; Côté latéral externe: 0 cm; Côté latéral interne: 0 cm; IFC_Pset_Géométrie_Chambranle - Position: Aucun; Épaisseur Chambranle intérieur: 0 cm; Longueur Chambranle intérieur: 0 cm; Superposition Chambranle intérieur: 0 cm; Épaisseur Intrados: 0 cm; Épaisseur Chambranle extérieur: 0 cm; Largeur Chambranle extérieur: 0 cm; Superposition Chambranle extérieur: 0 cm; Épaisseur Intrados extérieur: 0 cm; Décalage séparation intrados: 0 cm; IFC_Pset_Géométrie_CORNICHE depuis profil - Position: Aucune; sets with these values: 2; IFC_Pset_Géométrie_CORNICHE Extérieure à partir d'un profil - Décalage: 0; Angle: 0 deg; Symétrie: no; Fermer: no; sets with these values: 2; IFC_Pset_Géométrie_BASE Extérieure à partir d'un profil - Angle: 0 deg; Symétrie: no; Côté: 0 cm; sets with these values: 2; IFC_Pset_Géométrie - Côté extérieur: 0; Invertir (dte/gche): no; Invertir (intérieur/extérieur): no; Forme: Rectangle; Largeur: 150.194 cm; Hauteur: 206.315 cm; Hauteur 2: 0 cm; Rayon Arc: 0 cm; Rayon Cercle: 0 cm; Demi-axe horizontal: 0 cm; Demi-axe vertical: 0 cm; IFC_Pset_Géométrie_GRILLE - décalage: 0 cm; Offset latéral: 0 cm; Décalage supérieur: 0 cm; Décalage inférieur: 0 cm; Nombre accrochages latéraux: 0; Nombre d'accrochages supérieurs: 0; Nombre accrochages inférieurs: 0; IFC_Pset_Géométrie_Niche - Présent: no; Stratigraphie: Paroi en béton armé [120,00]; Épaisseur: 12 cm; Alignement: Intérieur; Décalage: 0 cm; IFC_Pset_Système de Référence Altimétrique_INFÉRIEUR - NIVEAU: Niveau 1 (Niveau 1 2343); delta: 0.0128504 cm; sous Niveau: <aucun>; IFC_Pset_Données Métré - Surface de l'Ouverture: 31000 cm2; Surface de l'Ébrasement: 0 cm2; Surface du Seuil: 0 cm2; Surface du Seuil intérieur: 0 cm2; Volume du seuil: 0 cm3; Volume du seuil intérieur: 0 cm3; Surface de la Niche: 0 cm2; Surface de la Grille: 0 cm2; Volume de la Grille: 0 cm3
Baie 442189 | Niveau 1 | 442189 | 114 | 9006 | 1 | -746779066 | Description: _VTO_Baie; CTLG_EXTERNAL_LINK - 1, DocType: 9; 1, Tag: 211; 1, Crc: -732809594; IFC_Pset_Caractéristiques - ID: 442189; Numérotation: 107; Numéro niveau: 04; Titre niveau: Niveau 1; IFC_Pset_Géométrie_Allège - Hauteur: 0 cm; Stratigraphie: ...; Épaisseur: 0 cm; IFC_Pset_Géométrie_Ébrasement - Présent: no; Côté supérieur: no; Côté INFÉRIEUR: no; Épaisseur extérieure: 0 cm; Épaisseur latérale gauche: 0 cm; Épaisseur latérale droite: 0 cm; Épiasseur latérale supérieure: 0 cm; Épaisseur diagonale gauche: 0 cm; Épaisseur diagonale droite: 0 cm; Épaisseur diagonale inférieure: 0 cm; Épaisseur diagonale supérieure: 0 cm; Épaisseur intérieur: 0 cm; IFC_Pset_Géométrie_Seuil - Type: Aucun; Épaisseur: 0 cm; Épaisseur interne: 0 cm; Décalage séparation: 0 cm; Appui extérieur: 0 cm; Appui intérieur: 0 cm; Côté latéral externe: 0 cm; Côté latéral interne: 0 cm; IFC_Pset_Géométrie_Chambranle - Position: Aucun; Épaisseur Chambranle intérieur: 0 cm; Longueur Chambranle intérieur: 0 cm; Superposition Chambranle intérieur: 0 cm; Épaisseur Intrados: 0 cm; Épaisseur Chambranle extérieur: 0 cm; Largeur Chambranle extérieur: 0 cm; Superposition Chambranle extérieur: 0 cm; Épaisseur Intrados extérieur: 0 cm; Décalage séparation intrados: 0 cm; IFC_Pset_Géométrie_CORNICHE depuis profil - Position: Aucune; sets with these values: 2; IFC_Pset_Géométrie_CORNICHE Extérieure à partir d'un profil - Décalage: 0; Angle: 0 deg; Symétrie: no; Fermer: no; sets with these values: 2; IFC_Pset_Géométrie_BASE Extérieure à partir d'un profil - Angle: 0 deg; Symétrie: no; Côté: 0 cm; sets with these values: 2; IFC_Pset_Géométrie - Côté extérieur: 1; Invertir (dte/gche): no; Invertir (intérieur/extérieur): yes; Forme: Rectangle; Largeur: 110.299 cm; Hauteur: 238 cm; Hauteur 2: 0 cm; Rayon Arc: 0 cm; Rayon Cercle: 0 cm; Demi-axe horizontal: 0 cm; Demi-axe vertical: 0 cm; IFC_Pset_Géométrie_GRILLE - décalage: 0 cm; Offset latéral: 0 cm; Décalage supérieur: 0 cm; Décalage inférieur: 0 cm; Nombre accrochages latéraux: 0; Nombre d'accrochages supérieurs: 0; Nombre accrochages inférieurs: 0; IFC_Pset_Géométrie_Niche - Présent: no; Stratigraphie: Paroi en béton armé [120,00]; Épaisseur: 12 cm; Alignement: Intérieur; Décalage: 0 cm; IFC_Pset_Système de Référence Altimétrique_INFÉRIEUR - NIVEAU: Niveau 1 (Niveau 1 2343); delta: 0.0128504 cm; sous Niveau: <aucun>; IFC_Pset_Données Métré - Surface de l'Ouverture: 26300 cm2; Surface de l'Ébrasement: 0 cm2; Surface du Seuil: 0 cm2; Surface du Seuil intérieur: 0 cm2; Volume du seuil: 0 cm3; Volume du seuil intérieur: 0 cm3; Surface de la Niche: 0 cm2; Surface de la Grille: 0 cm2; Volume de la Grille: 0 cm3
Baie 1528657 | Niveau 1 | 1528657 | 114 | 9006 | 1 | -746779066 | Description: _VTO_Baie; CTLG_EXTERNAL_LINK - 1, DocType: 9; 1, Tag: 211; 1, Crc: -1554559915; IFC_Pset_Caractéristiques - ID: 1528657; Numérotation: 169; Numéro niveau: 04; Titre niveau: Niveau 1; IFC_Pset_Géométrie_Allège - Hauteur: 0 cm; Stratigraphie: ...; Épaisseur: 0 cm; IFC_Pset_Géométrie_Ébrasement - Présent: no; Côté supérieur: no; Côté INFÉRIEUR: no; Épaisseur extérieure: 0 cm; Épaisseur latérale gauche: 0 cm; Épaisseur latérale droite: 0 cm; Épiasseur latérale supérieure: 0 cm; Épaisseur diagonale gauche: 0 cm; Épaisseur diagonale droite: 0 cm; Épaisseur diagonale inférieure: 0 cm; Épaisseur diagonale supérieure: 0 cm; Épaisseur intérieur: 0 cm; IFC_Pset_Géométrie_Seuil - Type: Aucun; Épaisseur: 0 cm; Épaisseur interne: 0 cm; Décalage séparation: 0 cm; Appui extérieur: 0 cm; Appui intérieur: 0 cm; Côté latéral externe: 0 cm; Côté latéral interne: 0 cm; IFC_Pset_Géométrie_Chambranle - Position: Aucun; Épaisseur Chambranle intérieur: 0 cm; Longueur Chambranle intérieur: 0 cm; Superposition Chambranle intérieur: 0 cm; Épaisseur Intrados: 0 cm; Épaisseur Chambranle extérieur: 0 cm; Largeur Chambranle extérieur: 0 cm; Superposition Chambranle extérieur: 0 cm; Épaisseur Intrados extérieur: 0 cm; Décalage séparation intrados: 0 cm; IFC_Pset_Géométrie_CORNICHE depuis profil - Position: Aucune; sets with these values: 2; IFC_Pset_Géométrie_CORNICHE Extérieure à partir d'un profil - Décalage: 0; Angle: 0 deg; Symétrie: no; Fermer: no; sets with these values: 2; IFC_Pset_Géométrie_BASE Extérieure à partir d'un profil - Angle: 0 deg; Symétrie: no; Côté: 0 cm; sets with these values: 2; IFC_Pset_Géométrie - Côté extérieur: 0; Invertir (dte/gche): no; Invertir (intérieur/extérieur): no; Forme: Rectangle; Largeur: 166.113 cm; Hauteur: 221.6 cm; Hauteur 2: 0 cm; Rayon Arc: 0 cm; Rayon Cercle: 0 cm; Demi-axe horizontal: 0 cm; Demi-axe vertical: 0 cm; IFC_Pset_Géométrie_GRILLE - décalage: 0 cm; Offset latéral: 0 cm; Décalage supérieur: 0 cm; Décalage inférieur: 0 cm; Nombre accrochages latéraux: 0; Nombre d'accrochages supérieurs: 0; Nombre accrochages inférieurs: 0; IFC_Pset_Géométrie_Niche - Présent: no; Stratigraphie: default [80,00]; Épaisseur: 8 cm; Alignement: Intérieur; Décalage: 0 cm; IFC_Pset_Système de Référence Altimétrique_INFÉRIEUR - NIVEAU: Niveau 1 (Niveau 1 2343); delta: 0.0128504 cm; sous Niveau: <aucun>; IFC_Pset_Données Métré - Surface de l'Ouverture: 36800 cm2; Surface de l'Ébrasement: 0 cm2; Surface du Seuil: 0 cm2; Surface du Seuil intérieur: 0 cm2; Volume du seuil: 0 cm3; Volume du seuil intérieur: 0 cm3; Surface de la Niche: 0 cm2; Surface de la Grille: 0 cm2; Volume de la Grille: 0 cm3
4294966486_11 | Niveau 1 | -810 | 2002 | 2002 | 0 | -1292786862
4294966487_11 | Niveau 1 | -809 | 2002 | 2002 | 0 | -1292786862
4294966414_11 | Niveau 1 | -882 | 2002 | 2002 | 0 | -1292786862
4294966510_11 | Niveau 1 | -786 | 2002 | 2002 | 0 | -1292786862
4294966469_11 | Niveau 1 | -827 | 2002 | 2002 | 0 | -1292786862
4294966423_11 | Niveau 1 | -873 | 2002 | 2002 | 0 | -1292786862
4294966427_11 | Niveau 1 | -869 | 2002 | 2002 | 0 | -1292786862
4294966395_11 | Niveau 1 | -901 | 2002 | 2002 | 0 | -1292786862
Baie 103103 | Niveau 1 | 103103 | 114 | 9006 | 1 | -746779066 | Description: _VTO_Baie; CTLG_EXTERNAL_LINK - 1, DocType: 9; 1, Tag: 211; 1, Crc: -732809594; IFC_Pset_Caractéristiques - ID: 103103; Numérotation: 027; Numéro niveau: 04; Titre niveau: Niveau 1; IFC_Pset_Géométrie_Allège - Hauteur: 0 cm; Stratigraphie: ...; Épaisseur: 0 cm; IFC_Pset_Géométrie_Ébrasement - Présent: no; Côté supérieur: no; Côté INFÉRIEUR: no; Épaisseur extérieure: 0 cm; Épaisseur latérale gauche: 0 cm; Épaisseur latérale droite: 0 cm; Épiasseur latérale supérieure: 0 cm; Épaisseur diagonale gauche: 0 cm; Épaisseur diagonale droite: 0 cm; Épaisseur diagonale inférieure: 0 cm; Épaisseur diagonale supérieure: 0 cm; Épaisseur intérieur: 0 cm; IFC_Pset_Géométrie_Seuil - Type: Aucun; Épaisseur: 0 cm; Épaisseur interne: 0 cm; Décalage séparation: 0 cm; Appui extérieur: 0 cm; Appui intérieur: 0 cm; Côté latéral externe: 0 cm; Côté latéral interne: 0 cm; IFC_Pset_Géométrie_Chambranle - Position: Aucun; Épaisseur Chambranle intérieur: 0 cm; Longueur Chambranle intérieur: 0 cm; Superposition Chambranle intérieur: 0 cm; Épaisseur Intrados: 0 cm; Épaisseur Chambranle extérieur: 0 cm; Largeur Chambranle extérieur: 0 cm; Superposition Chambranle extérieur: 0 cm; Épaisseur Intrados extérieur: 0 cm; Décalage séparation intrados: 0 cm; IFC_Pset_Géométrie_CORNICHE depuis profil - Position: Aucune; sets with these values: 2; IFC_Pset_Géométrie_CORNICHE Extérieure à partir d'un profil - Décalage: 0; Angle: 0 deg; Symétrie: no; Fermer: no; sets with these values: 2; IFC_Pset_Géométrie_BASE Extérieure à partir d'un profil - Angle: 0 deg; Symétrie: no; Côté: 0 cm; sets with these values: 2; IFC_Pset_Géométrie - Côté extérieur: 1; Invertir (dte/gche): no; Invertir (intérieur/extérieur): no; Forme: Arc + Rectangle; Largeur: 137 cm; Hauteur: 235 cm; Hauteur 2: 0 cm; Rayon Arc: 21.4062 cm; Rayon Cercle: 0 cm; Demi-axe horizontal: 0 cm; Demi-axe vertical: 0 cm; IFC_Pset_Géométrie_GRILLE - décalage: 0 cm; Offset latéral: 0 cm; Décalage supérieur: 0 cm; Décalage inférieur: 0 cm; Nombre accrochages latéraux: 0; Nombre d'accrochages supérieurs: 0; Nombre accrochages inférieurs: 0; IFC_Pset_Géométrie_Niche - Présent: no; Stratigraphie: Paroi en béton armé [120,00]; Épaisseur: 12 cm; Alignement: Intérieur; Décalage: 0 cm; IFC_Pset_Système de Référence Altimétrique_INFÉRIEUR - NIVEAU: Niveau 1 (Niveau 1 2343); delta: 0.0128504 cm; sous Niveau: <aucun>; IFC_Pset_Données Métré - Surface de l'Ouverture: 34200 cm2; Surface de l'Ébrasement: 0 cm2; Surface du Seuil: 0 cm2; Surface du Seuil intérieur: 0 cm2; Volume du seuil: 0 cm3; Volume du seuil intérieur: 0 cm3; Surface de la Niche: 0 cm2; Surface de la Grille: 0 cm2; Volume de la Grille: 0 cm3
4294966424_11 | Niveau 1 | -872 | 2002 | 2002 | 0 | -1292786862
4294966366_11 | Niveau 1 | -930 | 2002 | 2002 | 0 | -1292786862
4294966333_11 | Niveau 1 | -963 | 2002 | 2002 | 0 | -1292786862
4294966331_11 | Niveau 1 | -965 | 2002 | 2002 | 0 | -1292786862
4294966426_11 | Niveau 1 | -870 | 2002 | 2002 | 0 | -1292786862
4294966421_11 | Niveau 1 | -875 | 2002 | 2002 | 0 | -1292786862
4294966420_11 | Niveau 1 | -876 | 2002 | 2002 | 0 | -1292786862
4294966415_11 | Niveau 1 | -881 | 2002 | 2002 | 0 | -1292786862
4294966418_11 | Niveau 1 | -878 | 2002 | 2002 | 0 | -1292786862
4294966402_11 | Niveau 1 | -894 | 2002 | 2002 | 0 | -1292786862
4294966335_11 | Niveau 1 | -961 | 2002 | 2002 | 0 | -1292786862
4294966429_11 | Niveau 1 | -867 | 2002 | 2002 | 0 | -1292786862
4294966400_11 | Niveau 1 | -896 | 2002 | 2002 | 0 | -1292786862
4294966393_11 | Niveau 1 | -903 | 2002 | 2002 | 0 | -1292786862
4294966410_11 | Niveau 1 | -886 | 2002 | 2002 | 0 | -1292786862
4294966392_11 | Niveau 1 | -904 | 2002 | 2002 | 0 | -1292786862
4294966396_11 | Niveau 1 | -900 | 2002 | 2002 | 0 | -1292786862
4294966391_11 | Niveau 1 | -905 | 2002 | 2002 | 0 | -1292786862
Baie 115416 | Niveau 1 | 115416 | 114 | 9006 | 1 | -746779066 | Description: _VTO_Baie; CTLG_EXTERNAL_LINK - 1, DocType: 9; 1, Tag: 211; 1, Crc: -732809594; IFC_Pset_Caractéristiques - ID: 115416; Numérotation: 036; Numéro niveau: 04; Titre niveau: Niveau 1; IFC_Pset_Géométrie_Allège - Hauteur: 0 cm; Stratigraphie: ...; Épaisseur: 0 cm; IFC_Pset_Géométrie_Ébrasement - Présent: yes; Côté supérieur: no; Côté INFÉRIEUR: no; Épaisseur extérieure: 6 cm; Épaisseur latérale gauche: 6 cm; Épaisseur latérale droite: 6 cm; Épiasseur latérale supérieure: 6 cm; Épaisseur diagonale gauche: 1.5 cm; Épaisseur diagonale droite: 0 cm; Épaisseur diagonale inférieure: 1.5 cm; Épaisseur diagonale supérieure: 1.5 cm; Épaisseur intérieur: 6 cm; Données: [a : 60,00; b: 60,00; c: 15,00; d: 60,00] mm; IFC_Pset_Géométrie_Seuil - Type: Aucun; Épaisseur: 0 cm; Épaisseur interne: 0 cm; Décalage séparation: 0 cm; Appui extérieur: 0 cm; Appui intérieur: 0 cm; Côté latéral externe: 0 cm; Côté latéral interne: 0 cm; IFC_Pset_Géométrie_Chambranle - Position: Aucun; Épaisseur Chambranle intérieur: 0 cm; Longueur Chambranle intérieur: 0 cm; Superposition Chambranle intérieur: 0 cm; Épaisseur Intrados: 0 cm; Épaisseur Chambranle extérieur: 0 cm; Largeur Chambranle extérieur: 0 cm; Superposition Chambranle extérieur: 0 cm; Épaisseur Intrados extérieur: 0 cm; Décalage séparation intrados: 0 cm; IFC_Pset_Géométrie_CORNICHE depuis profil - Position: Aucune; sets with these values: 2; IFC_Pset_Géométrie_CORNICHE Extérieure à partir d'un profil - Décalage: 0; Angle: 0 deg; Symétrie: no; Fermer: no; sets with these values: 2; IFC_Pset_Géométrie_BASE Extérieure à partir d'un profil - Angle: 0 deg; Symétrie: no; Côté: 0 cm; sets with these values: 2; IFC_Pset_Géométrie - Côté extérieur: 0; Invertir (dte/gche): no; Invertir (intérieur/extérieur): no; Forme: Rectangle; Largeur: 69.079 cm; Hauteur: 199.489 cm; Hauteur 2: 0 cm; Rayon Arc: 0 cm; Rayon Cercle: 0 cm; Demi-axe horizontal: 0 cm; Demi-axe vertical: 0 cm; IFC_Pset_Géométrie_GRILLE - décalage: 0 cm; Offset latéral: 0 cm; Décalage supérieur: 0 cm; Décalage inférieur: 0 cm; Nombre accrochages latéraux: 0; Nombre d'accrochages supérieurs: 0; Nombre accrochages inférieurs: 0; IFC_Pset_Géométrie_Niche - Présent: no; Stratigraphie: Paroi en béton armé [120,00]; Épaisseur: 12 cm; Alignement: Intérieur; Décalage: 0 cm; IFC_Pset_Système de Référence Altimétrique_INFÉRIEUR - NIVEAU: Niveau 1 (Niveau 1 2343); delta: 0.0128504 cm; sous Niveau: <aucun>; IFC_Pset_Données Métré - Surface de l'Ouverture: 13800 cm2; Surface de l'Ébrasement: 27700 cm2; Surface du Seuil: 0 cm2; Surface du Seuil intérieur: 0 cm2; Volume du seuil: 0 cm3; Volume du seuil intérieur: 0 cm3; Surface de la Niche: 0 cm2; Surface de la Grille: 0 cm2; Volume de la Grille: 0 cm3
Baie 119698 | Niveau 1 | 119698 | 114 | 9006 | 1 | -746779066 | Description: _VTO_Baie; CTLG_EXTERNAL_LINK - 1, DocType: 9; 1, Tag: 211; 1, Crc: -106377247; IFC_Pset_Caractéristiques - ID: 119698; Numérotation: 038; Numéro niveau: 04; Titre niveau: Niveau 1; IFC_Pset_Géométrie_Allège - Hauteur: 0 cm; Stratigraphie: ...; Épaisseur: 0 cm; IFC_Pset_Géométrie_Ébrasement - Présent: no; Côté supérieur: no; Côté INFÉRIEUR: no; Épaisseur extérieure: 0 cm; Épaisseur latérale gauche: 0 cm; Épaisseur latérale droite: 0 cm; Épiasseur latérale supérieure: 0 cm; Épaisseur diagonale gauche: 0 cm; Épaisseur diagonale droite: 0 cm; Épaisseur diagonale inférieure: 0 cm; Épaisseur diagonale supérieure: 0 cm; Épaisseur intérieur: 0 cm; IFC_Pset_Géométrie_Seuil - Type: Aucun; Épaisseur: 0 cm; Épaisseur interne: 0 cm; Décalage séparation: 0 cm; Appui extérieur: 0 cm; Appui intérieur: 0 cm; Côté latéral externe: 0 cm; Côté latéral interne: 0 cm; IFC_Pset_Géométrie_Chambranle - Position: Aucun; Épaisseur Chambranle intérieur: 0 cm; Longueur Chambranle intérieur: 0 cm; Superposition Chambranle intérieur: 0 cm; Épaisseur Intrados: 0 cm; Épaisseur Chambranle extérieur: 0 cm; Largeur Chambranle extérieur: 0 cm; Superposition Chambranle extérieur: 0 cm; Épaisseur Intrados extérieur: 0 cm; Décalage séparation intrados: 0 cm; IFC_Pset_Géométrie_CORNICHE depuis profil - Position: Aucune; sets with these values: 2; IFC_Pset_Géométrie_CORNICHE Extérieure à partir d'un profil - Décalage: 0; Angle: 0 deg; Symétrie: no; Fermer: no; sets with these values: 2; IFC_Pset_Géométrie_BASE Extérieure à partir d'un profil - Angle: 0 deg; Symétrie: no; Côté: 0 cm; sets with these values: 2; IFC_Pset_Géométrie - Côté extérieur: 0; Invertir (dte/gche): no; Invertir (intérieur/extérieur): no; Forme: Arc + Rectangle; Largeur: 123.3 cm; Hauteur: 234.5 cm; Hauteur 2: 0 cm; Rayon Arc: 17.9978 cm; Rayon Cercle: 0 cm; Demi-axe horizontal: 0 cm; Demi-axe vertical: 0 cm; IFC_Pset_Géométrie_GRILLE - décalage: 0 cm; Offset latéral: 0 cm; Décalage supérieur: 0 cm; Décalage inférieur: 0 cm; Nombre accrochages latéraux: 0; Nombre d'accrochages supérieurs: 0; Nombre accrochages inférieurs: 0; IFC_Pset_Géométrie_Niche - Présent: no; Stratigraphie: default [140,00]; Épaisseur: 14 cm; Alignement: Intérieur; Décalage: 0 cm; IFC_Pset_Système de Référence Altimétrique_INFÉRIEUR - NIVEAU: Niveau 1 (Niveau 1 2343); delta: 0.0128504 cm; sous Niveau: <aucun>; IFC_Pset_Données Métré - Surface de l'Ouverture: 30400 cm2; Surface de l'Ébrasement: 0 cm2; Surface du Seuil: 0 cm2; Surface du Seuil intérieur: 0 cm2; Volume du seuil: 0 cm3; Volume du seuil intérieur: 0 cm3; Surface de la Niche: 0 cm2; Surface de la Grille: 0 cm2; Volume de la Grille: 0 cm3
Baie 132702 | Niveau 1 | 132702 | 114 | 9006 | 1 | -746779066 | Description: _VTO_Baie; CTLG_EXTERNAL_LINK - 1, DocType: 9; 1, Tag: 211; 1, Crc: -732809594; IFC_Pset_Caractéristiques - ID: 132702; Numérotation: 041; Numéro niveau: 04; Titre niveau: Niveau 1; IFC_Pset_Géométrie_Allège - Hauteur: 0 cm; Stratigraphie: ...; Épaisseur: 0 cm; IFC_Pset_Géométrie_Ébrasement - Présent: yes; Côté supérieur: no; Côté INFÉRIEUR: no; Épaisseur extérieure: 8 cm; Épaisseur latérale gauche: 5 cm; Épaisseur latérale droite: 5 cm; Épiasseur latérale supérieure: 5 cm; Épaisseur diagonale gauche: 2.5 cm; Épaisseur diagonale droite: 2.5 cm; Épaisseur diagonale inférieure: 2.5 cm; Épaisseur diagonale supérieure: 2.5 cm; Épaisseur intérieur: 6 cm; Données: [a : 80,00; b: 50,00; c: 25,00; d: 60,00] mm; IFC_Pset_Géométrie_Seuil - Type: Aucun; Épaisseur: 0 cm; Épaisseur interne: 0 cm; Décalage séparation: 0 cm; Appui extérieur: 0 cm; Appui intérieur: 0 cm; Côté latéral externe: 0 cm; Côté latéral interne: 0 cm; IFC_Pset_Géométrie_Chambranle - Position: Aucun; Épaisseur Chambranle intérieur: 0 cm; Longueur Chambranle intérieur: 0 cm; Superposition Chambranle intérieur: 0 cm; Épaisseur Intrados: 0 cm; Épaisseur Chambranle extérieur: 0 cm; Largeur Chambranle extérieur: 0 cm; Superposition Chambranle extérieur: 0 cm; Épaisseur Intrados extérieur: 0 cm; Décalage séparation intrados: 0 cm; IFC_Pset_Géométrie_CORNICHE depuis profil - Position: Aucune; sets with these values: 2; IFC_Pset_Géométrie_CORNICHE Extérieure à partir d'un profil - Décalage: 0; Angle: 0 deg; Symétrie: no; Fermer: no; sets with these values: 2; IFC_Pset_Géométrie_BASE Extérieure à partir d'un profil - Angle: 0 deg; Symétrie: no; Côté: 0 cm; sets with these values: 2; IFC_Pset_Géométrie - Côté extérieur: 0; Invertir (dte/gche): no; Invertir (intérieur/extérieur): no; Forme: Rectangle; Largeur: 99.5353 cm; Hauteur: 51 cm; Hauteur 2: 0 cm; Rayon Arc: 0 cm; Rayon Cercle: 0 cm; Demi-axe horizontal: 0 cm; Demi-axe vertical: 0 cm; IFC_Pset_Géométrie_GRILLE - décalage: 0 cm; Offset latéral: 0 cm; Décalage supérieur: 0 cm; Décalage inférieur: 0 cm; Nombre accrochages latéraux: 0; Nombre d'accrochages supérieurs: 0; Nombre accrochages inférieurs: 0; IFC_Pset_Géométrie_Niche - Présent: no; Stratigraphie: Paroi en béton armé [120,00]; Épaisseur: 12 cm; Alignement: Intérieur; Décalage: 0 cm; IFC_Pset_Système de Référence Altimétrique_INFÉRIEUR - NIVEAU: Niveau 1 (Niveau 1 2343); delta: 0.0128504 cm; sous Niveau: <aucun>; IFC_Pset_Données Métré - Surface de l'Ouverture: 5100 cm2; Surface de l'Ébrasement: 4600 cm2; Surface du Seuil: 0 cm2; Surface du Seuil intérieur: 0 cm2; Volume du seuil: 0 cm3; Volume du seuil intérieur: 0 cm3; Surface de la Niche: 0 cm2; Surface de la Grille: 0 cm2; Volume de la Grille: 0 cm3
4294966442_11 | Niveau 1 | -854 | 2002 | 2002 | 0 | -1292786862
Baie 132777 | Niveau 1 | 132777 | 114 | 9006 | 1 | -746779066 | Description: _VTO_Baie; CTLG_EXTERNAL_LINK - 1, DocType: 9; 1, Tag: 211; 1, Crc: -732809594; IFC_Pset_Caractéristiques - ID: 132777; Numérotation: 042; Numéro niveau: 04; Titre niveau: Niveau 1; IFC_Pset_Géométrie_Allège - Hauteur: 0 cm; Stratigraphie: ...; Épaisseur: 0 cm; IFC_Pset_Géométrie_Ébrasement - Présent: yes; Côté supérieur: no; Côté INFÉRIEUR: no; Épaisseur extérieure: 8 cm; Épaisseur latérale gauche: 5 cm; Épaisseur latérale droite: 5 cm; Épiasseur latérale supérieure: 5 cm; Épaisseur diagonale gauche: 2.5 cm; Épaisseur diagonale droite: 2.5 cm; Épaisseur diagonale inférieure: 2.5 cm; Épaisseur diagonale supérieure: 2.5 cm; Épaisseur intérieur: 6 cm; Données: [a : 80,00; b: 50,00; c: 25,00; d: 60,00] mm; IFC_Pset_Géométrie_Seuil - Type: Aucun; Épaisseur: 0 cm; Épaisseur interne: 0 cm; Décalage séparation: 0 cm; Appui extérieur: 0 cm; Appui intérieur: 0 cm; Côté latéral externe: 0 cm; Côté latéral interne: 0 cm; IFC_Pset_Géométrie_Chambranle - Position: Aucun; Épaisseur Chambranle intérieur: 0 cm; Longueur Chambranle intérieur: 0 cm; Superposition Chambranle intérieur: 0 cm; Épaisseur Intrados: 0 cm; Épaisseur Chambranle extérieur: 0 cm; Largeur Chambranle extérieur: 0 cm; Superposition Chambranle extérieur: 0 cm; Épaisseur Intrados extérieur: 0 cm; Décalage séparation intrados: 0 cm; IFC_Pset_Géométrie_CORNICHE depuis profil - Position: Aucune; sets with these values: 2; IFC_Pset_Géométrie_CORNICHE Extérieure à partir d'un profil - Décalage: 0; Angle: 0 deg; Symétrie: no; Fermer: no; sets with these values: 2; IFC_Pset_Géométrie_BASE Extérieure à partir d'un profil - Angle: 0 deg; Symétrie: no; Côté: 0 cm; sets with these values: 2; IFC_Pset_Géométrie - Côté extérieur: 1; Invertir (dte/gche): no; Invertir (intérieur/extérieur): no; Forme: Rectangle; Largeur: 99.2698 cm; Hauteur: 48 cm; Hauteur 2: 0 cm; Rayon Arc: 0 cm; Rayon Cercle: 0 cm; Demi-axe horizontal: 0 cm; Demi-axe vertical: 0 cm; IFC_Pset_Géométrie_GRILLE - décalage: 0 cm; Offset latéral: 0 cm; Décalage supérieur: 0 cm; Décalage inférieur: 0 cm; Nombre accrochages latéraux: 0; Nombre d'accrochages supérieurs: 0; Nombre accrochages inférieurs: 0; IFC_Pset_Géométrie_Niche - Présent: no; Stratigraphie: Paroi en béton armé [120,00]; Épaisseur: 12 cm; Alignement: Intérieur; Décalage: 0 cm; IFC_Pset_Système de Référence Altimétrique_INFÉRIEUR - NIVEAU: Niveau 1 (Niveau 1 2343); delta: 1.78551 cm; sous Niveau: <aucun>; IFC_Pset_Données Métré - Surface de l'Ouverture: 4800 cm2; Surface de l'Ébrasement: 4300 cm2; Surface du Seuil: 0 cm2; Surface du Seuil intérieur: 0 cm2; Volume du seuil: 0 cm3; Volume du seuil intérieur: 0 cm3; Surface de la Niche: 0 cm2; Surface de la Grille: 0 cm2; Volume de la Grille: 0 cm3
4294966430_11 | Niveau 1 | -866 | 2002 | 2002 | 0 | -1292786862
Baie 132859 | Niveau 1 | 132859 | 114 | 9006 | 1 | -746779066 | Description: _VTO_Baie; CTLG_EXTERNAL_LINK - 1, DocType: 9; 1, Tag: 211; 1, Crc: -732809594; IFC_Pset_Caractéristiques - ID: 132859; Numérotation: 043; Numéro niveau: 04; Titre niveau: Niveau 1; IFC_Pset_Géométrie_Allège - Hauteur: 0 cm; Stratigraphie: ...; Épaisseur: 0 cm; IFC_Pset_Géométrie_Ébrasement - Présent: yes; Côté supérieur: no; Côté INFÉRIEUR: no; Épaisseur extérieure: 8 cm; Épaisseur latérale gauche: 5 cm; Épaisseur latérale droite: 5 cm; Épiasseur latérale supérieure: 5 cm; Épaisseur diagonale gauche: 2.5 cm; Épaisseur diagonale droite: 2.5 cm; Épaisseur diagonale inférieure: 2.5 cm; Épaisseur diagonale supérieure: 2.5 cm; Épaisseur intérieur: 6 cm; Données: [a : 80,00; b: 50,00; c: 25,00; d: 60,00] mm; IFC_Pset_Géométrie_Seuil - Type: Aucun; Épaisseur: 0 cm; Épaisseur interne: 0 cm; Décalage séparation: 0 cm; Appui extérieur: 0 cm; Appui intérieur: 0 cm; Côté latéral externe: 0 cm; Côté latéral interne: 0 cm; IFC_Pset_Géométrie_Chambranle - Position: Aucun; Épaisseur Chambranle intérieur: 0 cm; Longueur Chambranle intérieur: 0 cm; Superposition Chambranle intérieur: 0 cm; Épaisseur Intrados: 0 cm; Épaisseur Chambranle extérieur: 0 cm; Largeur Chambranle extérieur: 0 cm; Superposition Chambranle extérieur: 0 cm; Épaisseur Intrados extérieur: 0 cm; Décalage séparation intrados: 0 cm; IFC_Pset_Géométrie_CORNICHE depuis profil - Position: Aucune; sets with these values: 2; IFC_Pset_Géométrie_CORNICHE Extérieure à partir d'un profil - Décalage: 0; Angle: 0 deg; Symétrie: no; Fermer: no; sets with these values: 2; IFC_Pset_Géométrie_BASE Extérieure à partir d'un profil - Angle: 0 deg; Symétrie: no; Côté: 0 cm; sets with these values: 2; IFC_Pset_Géométrie - Côté extérieur: 1; Invertir (dte/gche): no; Invertir (intérieur/extérieur): no; Forme: Rectangle; Largeur: 96.4014 cm; Hauteur: 48 cm; Hauteur 2: 0 cm; Rayon Arc: 0 cm; Rayon Cercle: 0 cm; Demi-axe horizontal: 0 cm; Demi-axe vertical: 0 cm; IFC_Pset_Géométrie_GRILLE - décalage: 0 cm; Offset latéral: 0 cm; Décalage supérieur: 0 cm; Décalage inférieur: 0 cm; Nombre accrochages latéraux: 0; Nombre d'accrochages supérieurs: 0; Nombre accrochages inférieurs: 0; IFC_Pset_Géométrie_Niche - Présent: no; Stratigraphie: Paroi en béton armé [120,00]; Épaisseur: 12 cm; Alignement: Intérieur; Décalage: 0 cm; IFC_Pset_Système de Référence Altimétrique_INFÉRIEUR - NIVEAU: Niveau 1 (Niveau 1 2343); delta: 0.0128504 cm; sous Niveau: <aucun>; IFC_Pset_Données Métré - Surface de l'Ouverture: 4600 cm2; Surface de l'Ébrasement: 4300 cm2; Surface du Seuil: 0 cm2; Surface du Seuil intérieur: 0 cm2; Volume du seuil: 0 cm3; Volume du seuil intérieur: 0 cm3; Surface de la Niche: 0 cm2; Surface de la Grille: 0 cm2; Volume de la Grille: 0 cm3
4294966441_11 | Niveau 1 | -855 | 2002 | 2002 | 0 | -1292786862
4294966419_11 | Niveau 1 | -877 | 2002 | 2002 | 0 | -1292786862
4294966334_11 | Niveau 1 | -962 | 2002 | 2002 | 0 | -1292786862
4294966409_11 | Niveau 1 | -887 | 2002 | 2002 | 0 | -1292786862
4294966411_11 | Niveau 1 | -885 | 2002 | 2002 | 0 | -1292786862
4294966413_11 | Niveau 1 | -883 | 2002 | 2002 | 0 | -1292786862
Baie 442635 | Niveau 1 | 442635 | 114 | 9006 | 1 | -746779066 | Description: _VTO_Baie; CTLG_EXTERNAL_LINK - 1, DocType: 9; 1, Tag: 211; 1, Crc: -732809594; IFC_Pset_Caractéristiques - ID: 442635; Numérotation: 110; Numéro niveau: 04; Titre niveau: Niveau 1; IFC_Pset_Géométrie_Allège - Hauteur: 0 cm; Stratigraphie: ...; Épaisseur: 0 cm; IFC_Pset_Géométrie_Ébrasement - Présent: yes; Côté supérieur: no; Côté INFÉRIEUR: no; Épaisseur extérieure: 11 cm; Épaisseur latérale gauche: 3 cm; Épaisseur latérale droite: 3 cm; Épiasseur latérale supérieure: 3 cm; Épaisseur diagonale gauche: 0 cm; Épaisseur diagonale droite: 0 cm; Épaisseur diagonale inférieure: 0 cm; Épaisseur diagonale supérieure: 0 cm; Épaisseur intérieur: 0 cm; Données: [a : 110,00; b: 30,00; c: 0,00; d: 0,00] mm; IFC_Pset_Géométrie_Seuil - Type: Aucun; Épaisseur: 0 cm; Épaisseur interne: 0 cm; Décalage séparation: 0 cm; Appui extérieur: 0 cm; Appui intérieur: 0 cm; Côté latéral externe: 0 cm; Côté latéral interne: 0 cm; IFC_Pset_Géométrie_Chambranle - Position: Aucun; Épaisseur Chambranle intérieur: 0 cm; Longueur Chambranle intérieur: 0 cm; Superposition Chambranle intérieur: 0 cm; Épaisseur Intrados: 0 cm; Épaisseur Chambranle extérieur: 0 cm; Largeur Chambranle extérieur: 0 cm; Superposition Chambranle extérieur: 0 cm; Épaisseur Intrados extérieur: 0 cm; Décalage séparation intrados: 0 cm; IFC_Pset_Géométrie_CORNICHE depuis profil - Position: Aucune; sets with these values: 2; IFC_Pset_Géométrie_CORNICHE Extérieure à partir d'un profil - Décalage: 0; Angle: 0 deg; Symétrie: no; Fermer: no; sets with these values: 2; IFC_Pset_Géométrie_BASE Extérieure à partir d'un profil - Angle: 0 deg; Symétrie: no; Côté: 0 cm; sets with these values: 2; IFC_Pset_Géométrie - Côté extérieur: 0; Invertir (dte/gche): no; Invertir (intérieur/extérieur): no; Forme: Rectangle; Largeur: 110.938 cm; Hauteur: 295.848 cm; Hauteur 2: 0 cm; Rayon Arc: 0 cm; Rayon Cercle: 0 cm; Demi-axe horizontal: 0 cm; Demi-axe vertical: 0 cm; IFC_Pset_Géométrie_GRILLE - décalage: 0 cm; Offset latéral: 0 cm; Décalage supérieur: 0 cm; Décalage inférieur: 0 cm; Nombre accrochages latéraux: 0; Nombre d'accrochages supérieurs: 0; Nombre accrochages inférieurs: 0; IFC_Pset_Géométrie_Niche - Présent: no; Stratigraphie: Paroi en béton armé [120,00]; Épaisseur: 12 cm; Alignement: Intérieur; Décalage: 0 cm; IFC_Pset_Système de Référence Altimétrique_INFÉRIEUR - NIVEAU: Niveau 1 (Niveau 1 2343); delta: 0.0128504 cm; sous Niveau: <aucun>; IFC_Pset_Données Métré - Surface de l'Ouverture: 32800 cm2; Surface de l'Ébrasement: 10700 cm2; Surface du Seuil: 0 cm2; Surface du Seuil intérieur: 0 cm2; Volume du seuil: 0 cm3; Volume du seuil intérieur: 0 cm3; Surface de la Niche: 0 cm2; Surface de la Grille: 0 cm2; Volume de la Grille: 0 cm3
4294966471_11 | Niveau 1 | -825 | 2002 | 2002 | 0 | -1292786862
4294966468_11 | Niveau 1 | -828 | 2002 | 2002 | 0 | -1292786862
4294966417_11 | Niveau 1 | -879 | 2002 | 2002 | 0 | -1292786862
4294966416_11 | Niveau 1 | -880 | 2002 | 2002 | 0 | -1292786862
4294966341_11 | Niveau 1 | -955 | 2002 | 2002 | 0 | -1292786862
4294966425_11 | Niveau 1 | -871 | 2002 | 2002 | 0 | -1292786862
4294966422_11 | Niveau 1 | -874 | 2002 | 2002 | 0 | -1292786862
4294966401_11 | Niveau 1 | -895 | 2002 | 2002 | 0 | -1292786862
4294966399_11 | Niveau 1 | -897 | 2002 | 2002 | 0 | -1292786862
4294966428_11 | Niveau 1 | -868 | 2002 | 2002 | 0 | -1292786862
Baie 121126 | Niveau 1 | 121126 | 114 | 9006 | 1 | -746779066 | Description: _VTO_Baie; CTLG_EXTERNAL_LINK - 1, DocType: 9; 1, Tag: 211; 1, Crc: -662831384; IFC_Pset_Caractéristiques - ID: 121126; Numérotation: 040; Numéro niveau: 04; Titre niveau: Niveau 1; IFC_Pset_Géométrie_Allège - Hauteur: 0 cm; Stratigraphie: ...; Épaisseur: 0 cm; IFC_Pset_Géométrie_Ébrasement - Présent: no; Côté supérieur: no; Côté INFÉRIEUR: no; Épaisseur extérieure: 0 cm; Épaisseur latérale gauche: 0 cm; Épaisseur latérale droite: 0 cm; Épiasseur latérale supérieure: 0 cm; Épaisseur diagonale gauche: 0 cm; Épaisseur diagonale droite: 0 cm; Épaisseur diagonale inférieure: 0 cm; Épaisseur diagonale supérieure: 0 cm; Épaisseur intérieur: 0 cm; IFC_Pset_Géométrie_Seuil - Type: Aucun; Épaisseur: 0 cm; Épaisseur interne: 0 cm; Décalage séparation: 0 cm; Appui extérieur: 0 cm; Appui intérieur: 0 cm; Côté latéral externe: 0 cm; Côté latéral interne: 0 cm; IFC_Pset_Géométrie_Chambranle - Position: Aucun; Épaisseur Chambranle intérieur: 0 cm; Longueur Chambranle intérieur: 0 cm; Superposition Chambranle intérieur: 0 cm; Épaisseur Intrados: 0 cm; Épaisseur Chambranle extérieur: 0 cm; Largeur Chambranle extérieur: 0 cm; Superposition Chambranle extérieur: 0 cm; Épaisseur Intrados extérieur: 0 cm; Décalage séparation intrados: 0 cm; IFC_Pset_Géométrie_CORNICHE depuis profil - Position: Aucune; sets with these values: 2; IFC_Pset_Géométrie_CORNICHE Extérieure à partir d'un profil - Décalage: 0; Angle: 0 deg; Symétrie: no; Fermer: no; sets with these values: 2; IFC_Pset_Géométrie_BASE Extérieure à partir d'un profil - Angle: 0 deg; Symétrie: no; Côté: 0 cm; sets with these values: 2; IFC_Pset_Géométrie - Côté extérieur: 0; Invertir (dte/gche): no; Invertir (intérieur/extérieur): no; Forme: Rectangle; Largeur: 136.644 cm; Hauteur: 205 cm; Hauteur 2: 0 cm; Rayon Arc: 0 cm; Rayon Cercle: 0 cm; Demi-axe horizontal: 0 cm; Demi-axe vertical: 0 cm; IFC_Pset_Géométrie_GRILLE - décalage: 0 cm; Offset latéral: 0 cm; Décalage supérieur: 0 cm; Décalage inférieur: 0 cm; Nombre accrochages latéraux: 0; Nombre d'accrochages supérieurs: 0; Nombre accrochages inférieurs: 0; IFC_Pset_Géométrie_Niche - Présent: no; Stratigraphie: default [60,00]; Épaisseur: 6 cm; Alignement: Intérieur; Décalage: 0 cm; IFC_Pset_Système de Référence Altimétrique_INFÉRIEUR - NIVEAU: Niveau 1 (Niveau 1 2343); delta: 8 cm; sous Niveau: <aucun>; IFC_Pset_Données Métré - Surface de l'Ouverture: 28000 cm2; Surface de l'Ébrasement: 0 cm2; Surface du Seuil: 0 cm2; Surface du Seuil intérieur: 0 cm2; Volume du seuil: 0 cm3; Volume du seuil intérieur: 0 cm3; Surface de la Niche: 0 cm2; Surface de la Grille: 0 cm2; Volume de la Grille: 0 cm3
4294966394_11 | Niveau 1 | -902 | 2002 | 2002 | 0 | -1292786862
4294966398_11 | Niveau 1 | -898 | 2002 | 2002 | 0 | -1292786862
4294966397_11 | Niveau 1 | -899 | 2002 | 2002 | 0 | -1292786862
4294966340_11 | Niveau 1 | -956 | 2002 | 2002 | 0 | -1292786862
Baie 103100 | Niveau 1 | 103100 | 114 | 9006 | 1 | -746779066 | Description: _VTO_Baie; CTLG_EXTERNAL_LINK - 1, DocType: 9; 1, Tag: 211; 1, Crc: -732809594; IFC_Pset_Caractéristiques - ID: 103100; Numérotation: 026; Numéro niveau: 04; Titre niveau: Niveau 1; IFC_Pset_Géométrie_Allège - Hauteur: 0 cm; Stratigraphie: ...; Épaisseur: 0 cm; IFC_Pset_Géométrie_Ébrasement - Présent: no; Côté supérieur: no; Côté INFÉRIEUR: no; Épaisseur extérieure: 0 cm; Épaisseur latérale gauche: 0 cm; Épaisseur latérale droite: 0 cm; Épiasseur latérale supérieure: 0 cm; Épaisseur diagonale gauche: 0 cm; Épaisseur diagonale droite: 0 cm; Épaisseur diagonale inférieure: 0 cm; Épaisseur diagonale supérieure: 0 cm; Épaisseur intérieur: 0 cm; IFC_Pset_Géométrie_Seuil - Type: Aucun; Épaisseur: 0 cm; Épaisseur interne: 0 cm; Décalage séparation: 0 cm; Appui extérieur: 0 cm; Appui intérieur: 0 cm; Côté latéral externe: 0 cm; Côté latéral interne: 0 cm; IFC_Pset_Géométrie_Chambranle - Position: Aucun; Épaisseur Chambranle intérieur: 0 cm; Longueur Chambranle intérieur: 0 cm; Superposition Chambranle intérieur: 0 cm; Épaisseur Intrados: 0 cm; Épaisseur Chambranle extérieur: 0 cm; Largeur Chambranle extérieur: 0 cm; Superposition Chambranle extérieur: 0 cm; Épaisseur Intrados extérieur: 0 cm; Décalage séparation intrados: 0 cm; IFC_Pset_Géométrie_CORNICHE depuis profil - Position: Aucune; sets with these values: 2; IFC_Pset_Géométrie_CORNICHE Extérieure à partir d'un profil - Décalage: 0; Angle: 0 deg; Symétrie: no; Fermer: no; sets with these values: 2; IFC_Pset_Géométrie_BASE Extérieure à partir d'un profil - Angle: 0 deg; Symétrie: no; Côté: 0 cm; sets with these values: 2; IFC_Pset_Géométrie - Côté extérieur: 1; Invertir (dte/gche): no; Invertir (intérieur/extérieur): no; Forme: Rectangle; Largeur: 113 cm; Hauteur: 235 cm; Hauteur 2: 0 cm; Rayon Arc: 0 cm; Rayon Cercle: 0 cm; Demi-axe horizontal: 0 cm; Demi-axe vertical: 0 cm; IFC_Pset_Géométrie_GRILLE - décalage: 0 cm; Offset latéral: 0 cm; Décalage supérieur: 0 cm; Décalage inférieur: 0 cm; Nombre accrochages latéraux: 0; Nombre d'accrochages supérieurs: 0; Nombre accrochages inférieurs: 0; IFC_Pset_Géométrie_Niche - Présent: no; Stratigraphie: Paroi en béton armé [120,00]; Épaisseur: 12 cm; Alignement: Intérieur; Décalage: 0 cm; IFC_Pset_Système de Référence Altimétrique_INFÉRIEUR - NIVEAU: Niveau 1 (Niveau 1 2343); delta: 0.0128504 cm; sous Niveau: <aucun>; IFC_Pset_Données Métré - Surface de l'Ouverture: 26600 cm2; Surface de l'Ébrasement: 0 cm2; Surface du Seuil: 0 cm2; Surface du Seuil intérieur: 0 cm2; Volume du seuil: 0 cm3; Volume du seuil intérieur: 0 cm3; Surface de la Niche: 0 cm2; Surface de la Grille: 0 cm2; Volume de la Grille: 0 cm3
4294966336_11 | Niveau 1 | -960 | 2002 | 2002 | 0 | -1292786862
4294966332_11 | Niveau 1 | -964 | 2002 | 2002 | 0 | -1292786862
4294966412_11 | Niveau 1 | -884 | 2002 | 2002 | 0 | -1292786862
4294966445_11 | Niveau 2 | -851 | 2002 | 2002 | 0 | -1292786862
Baie 2052964 | Niveau 2 | 2052964 | 114 | 9006 | 1 | -746779066 | Description: _VTO_Baie; CTLG_EXTERNAL_LINK - 1, DocType: 9; 1, Tag: 211; 1, Crc: -732809594; IFC_Pset_Caractéristiques - ID: 2052964; Numérotation: 173; Numéro niveau: 05; Titre niveau: Niveau 2; IFC_Pset_Géométrie_Allège - Hauteur: 0 cm; Stratigraphie: ...; Épaisseur: 0 cm; IFC_Pset_Géométrie_Ébrasement - Présent: no; Côté supérieur: no; Côté INFÉRIEUR: no; Épaisseur extérieure: 0 cm; Épaisseur latérale gauche: 0 cm; Épaisseur latérale droite: 0 cm; Épiasseur latérale supérieure: 0 cm; Épaisseur diagonale gauche: 0 cm; Épaisseur diagonale droite: 0 cm; Épaisseur diagonale inférieure: 0 cm; Épaisseur diagonale supérieure: 0 cm; Épaisseur intérieur: 0 cm; IFC_Pset_Géométrie_Seuil - Type: Aucun; Épaisseur: 0 cm; Épaisseur interne: 0 cm; Décalage séparation: 0 cm; Appui extérieur: 0 cm; Appui intérieur: 0 cm; Côté latéral externe: 0 cm; Côté latéral interne: 0 cm; IFC_Pset_Géométrie_Chambranle - Position: Aucun; Épaisseur Chambranle intérieur: 0 cm; Longueur Chambranle intérieur: 0 cm; Superposition Chambranle intérieur: 0 cm; Épaisseur Intrados: 0 cm; Épaisseur Chambranle extérieur: 0 cm; Largeur Chambranle extérieur: 0 cm; Superposition Chambranle extérieur: 0 cm; Épaisseur Intrados extérieur: 0 cm; Décalage séparation intrados: 0 cm; IFC_Pset_Géométrie_CORNICHE depuis profil - Position: Aucune; sets with these values: 2; IFC_Pset_Géométrie_CORNICHE Extérieure à partir d'un profil - Décalage: 0; Angle: 0 deg; Symétrie: no; Fermer: no; sets with these values: 2; IFC_Pset_Géométrie_BASE Extérieure à partir d'un profil - Angle: 0 deg; Symétrie: no; Côté: 0 cm; sets with these values: 2; IFC_Pset_Géométrie - Côté extérieur: 1; Invertir (dte/gche): no; Invertir (intérieur/extérieur): yes; Forme: Rectangle; Largeur: 107.648 cm; Hauteur: 100 cm; Hauteur 2: 0 cm; Rayon Arc: 0 cm; Rayon Cercle: 0 cm; Demi-axe horizontal: 0 cm; Demi-axe vertical: 0 cm; IFC_Pset_Géométrie_GRILLE - décalage: 0 cm; Offset latéral: 0 cm; Décalage supérieur: 0 cm; Décalage inférieur: 0 cm; Nombre accrochages latéraux: 0; Nombre d'accrochages supérieurs: 0; Nombre accrochages inférieurs: 0; IFC_Pset_Géométrie_Niche - Présent: no; Stratigraphie: Paroi en béton armé [120,00]; Épaisseur: 12 cm; Alignement: Intérieur; Décalage: 0 cm; IFC_Pset_Système de Référence Altimétrique_INFÉRIEUR - NIVEAU: Niveau 2 (Niveau 2 13545); delta: 94 cm; sous Niveau: <aucun>; IFC_Pset_Données Métré - Surface de l'Ouverture: 10800 cm2; Surface de l'Ébrasement: 0 cm2; Surface du Seuil: 0 cm2; Surface du Seuil intérieur: 0 cm2; Volume du seuil: 0 cm3; Volume du seuil intérieur: 0 cm3; Surface de la Niche: 0 cm2; Surface de la Grille: 0 cm2; Volume de la Grille: 0 cm3
Baie 748553 | Niveau 2 | 748553 | 114 | 9006 | 1 | -746779066 | Description: _VTO_Baie; CTLG_EXTERNAL_LINK - 1, DocType: 9; 1, Tag: 211; 1, Crc: -732809594; IFC_Pset_Caractéristiques - ID: 748553; Numérotation: 151; Numéro niveau: 05; Titre niveau: Niveau 2; IFC_Pset_Géométrie_Allège - Hauteur: 0 cm; Stratigraphie: ...; Épaisseur: 0 cm; IFC_Pset_Géométrie_Ébrasement - Présent: yes; Côté supérieur: no; Côté INFÉRIEUR: no; Épaisseur extérieure: 11 cm; Épaisseur latérale gauche: 3 cm; Épaisseur latérale droite: 3 cm; Épiasseur latérale supérieure: 3 cm; Épaisseur diagonale gauche: 0 cm; Épaisseur diagonale droite: 0 cm; Épaisseur diagonale inférieure: 0 cm; Épaisseur diagonale supérieure: 0 cm; Épaisseur intérieur: 0 cm; Données: [a : 110,00; b: 30,00; c: 0,00; d: 0,00] mm; IFC_Pset_Géométrie_Seuil - Type: Aucun; Épaisseur: 0 cm; Épaisseur interne: 0 cm; Décalage séparation: 0 cm; Appui extérieur: 0 cm; Appui intérieur: 0 cm; Côté latéral externe: 0 cm; Côté latéral interne: 0 cm; IFC_Pset_Géométrie_Chambranle - Position: Aucun; Épaisseur Chambranle intérieur: 0 cm; Longueur Chambranle intérieur: 0 cm; Superposition Chambranle intérieur: 0 cm; Épaisseur Intrados: 0 cm; Épaisseur Chambranle extérieur: 0 cm; Largeur Chambranle extérieur: 0 cm; Superposition Chambranle extérieur: 0 cm; Épaisseur Intrados extérieur: 0 cm; Décalage séparation intrados: 0 cm; IFC_Pset_Géométrie_CORNICHE depuis profil - Position: Aucune; sets with these values: 2; IFC_Pset_Géométrie_CORNICHE Extérieure à partir d'un profil - Décalage: 0; Angle: 0 deg; Symétrie: no; Fermer: no; sets with these values: 2; IFC_Pset_Géométrie_BASE Extérieure à partir d'un profil - Angle: 0 deg; Symétrie: no; Côté: 0 cm; sets with these values: 2; IFC_Pset_Géométrie - Côté extérieur: 0; Invertir (dte/gche): no; Invertir (intérieur/extérieur): no; Forme: Rectangle; Largeur: 101.084 cm; Hauteur: 176.823 cm; Hauteur 2: 0 cm; Rayon Arc: 0 cm; Rayon Cercle: 0 cm; Demi-axe horizontal: 0 cm; Demi-axe vertical: 0 cm; IFC_Pset_Géométrie_GRILLE - décalage: 0 cm; Offset latéral: 0 cm; Décalage supérieur: 0 cm; Décalage inférieur: 0 cm; Nombre accrochages latéraux: 0; Nombre d'accrochages supérieurs: 0; Nombre accrochages inférieurs: 0; IFC_Pset_Géométrie_Niche - Présent: no; Stratigraphie: Paroi en béton armé [120,00]; Épaisseur: 12 cm; Alignement: Intérieur; Décalage: 0 cm; IFC_Pset_Système de Référence Altimétrique_INFÉRIEUR - NIVEAU: Niveau 2 (Niveau 2 13545); delta: 49.9126 cm; sous Niveau: <aucun>; IFC_Pset_Données Métré - Surface de l'Ouverture: 17900 cm2; Surface de l'Ébrasement: 6400 cm2; Surface du Seuil: 0 cm2; Surface du Seuil intérieur: 0 cm2; Volume du seuil: 0 cm3; Volume du seuil intérieur: 0 cm3; Surface de la Niche: 0 cm2; Surface de la Grille: 0 cm2; Volume de la Grille: 0 cm3
Baie 748551 | Niveau 2 | 748551 | 114 | 9006 | 1 | -746779066 | Description: _VTO_Baie; CTLG_EXTERNAL_LINK - 1, DocType: 9; 1, Tag: 211; 1, Crc: -732809594; IFC_Pset_Caractéristiques - ID: 748551; Numérotation: 150; Numéro niveau: 05; Titre niveau: Niveau 2; IFC_Pset_Géométrie_Allège - Hauteur: 0 cm; Stratigraphie: ...; Épaisseur: 0 cm; IFC_Pset_Géométrie_Ébrasement - Présent: yes; Côté supérieur: no; Côté INFÉRIEUR: no; Épaisseur extérieure: 11 cm; Épaisseur latérale gauche: 3 cm; Épaisseur latérale droite: 3 cm; Épiasseur latérale supérieure: 3 cm; Épaisseur diagonale gauche: 0 cm; Épaisseur diagonale droite: 0 cm; Épaisseur diagonale inférieure: 0 cm; Épaisseur diagonale supérieure: 0 cm; Épaisseur intérieur: 0 cm; Données: [a : 110,00; b: 30,00; c: 0,00; d: 0,00] mm; IFC_Pset_Géométrie_Seuil - Type: Aucun; Épaisseur: 0 cm; Épaisseur interne: 0 cm; Décalage séparation: 0 cm; Appui extérieur: 0 cm; Appui intérieur: 0 cm; Côté latéral externe: 0 cm; Côté latéral interne: 0 cm; IFC_Pset_Géométrie_Chambranle - Position: Aucun; Épaisseur Chambranle intérieur: 0 cm; Longueur Chambranle intérieur: 0 cm; Superposition Chambranle intérieur: 0 cm; Épaisseur Intrados: 0 cm; Épaisseur Chambranle extérieur: 0 cm; Largeur Chambranle extérieur: 0 cm; Superposition Chambranle extérieur: 0 cm; Épaisseur Intrados extérieur: 0 cm; Décalage séparation intrados: 0 cm; IFC_Pset_Géométrie_CORNICHE depuis profil - Position: Aucune; sets with these values: 2; IFC_Pset_Géométrie_CORNICHE Extérieure à partir d'un profil - Décalage: 0; Angle: 0 deg; Symétrie: no; Fermer: no; sets with these values: 2; IFC_Pset_Géométrie_BASE Extérieure à partir d'un profil - Angle: 0 deg; Symétrie: no; Côté: 0 cm; sets with these values: 2; IFC_Pset_Géométrie - Côté extérieur: 1; Invertir (dte/gche): no; Invertir (intérieur/extérieur): yes; Forme: Rectangle; Largeur: 101.552 cm; Hauteur: 179.845 cm; Hauteur 2: 0 cm; Rayon Arc: 0 cm; Rayon Cercle: 0 cm; Demi-axe horizontal: 0 cm; Demi-axe vertical: 0 cm; IFC_Pset_Géométrie_GRILLE - décalage: 0 cm; Offset latéral: 0 cm; Décalage supérieur: 0 cm; Décalage inférieur: 0 cm; Nombre accrochages latéraux: 0; Nombre d'accrochages supérieurs: 0; Nombre accrochages inférieurs: 0; IFC_Pset_Géométrie_Niche - Présent: no; Stratigraphie: Paroi en béton armé [120,00]; Épaisseur: 12 cm; Alignement: Intérieur; Décalage: 0 cm; IFC_Pset_Système de Référence Altimétrique_INFÉRIEUR - NIVEAU: Niveau 2 (Niveau 2 13545); delta: 50.0713 cm; sous Niveau: <aucun>; IFC_Pset_Données Métré - Surface de l'Ouverture: 18300 cm2; Surface de l'Ébrasement: 6500 cm2; Surface du Seuil: 0 cm2; Surface du Seuil intérieur: 0 cm2; Volume du seuil: 0 cm3; Volume du seuil intérieur: 0 cm3; Surface de la Niche: 0 cm2; Surface de la Grille: 0 cm2; Volume de la Grille: 0 cm3
Baie 750772 | Niveau 2 | 750772 | 114 | 9006 | 1 | -746779066 | Description: _VTO_Baie; CTLG_EXTERNAL_LINK - 1, DocType: 9; 1, Tag: 211; 1, Crc: -732809594; IFC_Pset_Caractéristiques - ID: 750772; Numérotation: 157; Numéro niveau: 05; Titre niveau: Niveau 2; IFC_Pset_Géométrie_Allège - Hauteur: 0 cm; Stratigraphie: ...; Épaisseur: 0 cm; IFC_Pset_Géométrie_Ébrasement - Présent: yes; Côté supérieur: no; Côté INFÉRIEUR: no; Épaisseur extérieure: 11 cm; Épaisseur latérale gauche: 3 cm; Épaisseur latérale droite: 3 cm; Épiasseur latérale supérieure: 3 cm; Épaisseur diagonale gauche: 0 cm; Épaisseur diagonale droite: 0 cm; Épaisseur diagonale inférieure: 0 cm; Épaisseur diagonale supérieure: 0 cm; Épaisseur intérieur: 0 cm; Données: [a : 110,00; b: 30,00; c: 0,00; d: 0,00] mm; IFC_Pset_Géométrie_Seuil - Type: Aucun; Épaisseur: 0 cm; Épaisseur interne: 0 cm; Décalage séparation: 0 cm; Appui extérieur: 0 cm; Appui intérieur: 0 cm; Côté latéral externe: 0 cm; Côté latéral interne: 0 cm; IFC_Pset_Géométrie_Chambranle - Position: Aucun; Épaisseur Chambranle intérieur: 0 cm; Longueur Chambranle intérieur: 0 cm; Superposition Chambranle intérieur: 0 cm; Épaisseur Intrados: 0 cm; Épaisseur Chambranle extérieur: 0 cm; Largeur Chambranle extérieur: 0 cm; Superposition Chambranle extérieur: 0 cm; Épaisseur Intrados extérieur: 0 cm; Décalage séparation intrados: 0 cm; IFC_Pset_Géométrie_CORNICHE depuis profil - Position: Aucune; sets with these values: 2; IFC_Pset_Géométrie_CORNICHE Extérieure à partir d'un profil - Décalage: 0; Angle: 0 deg; Symétrie: no; Fermer: no; sets with these values: 2; IFC_Pset_Géométrie_BASE Extérieure à partir d'un profil - Angle: 0 deg; Symétrie: no; Côté: 0 cm; sets with these values: 2; IFC_Pset_Géométrie - Côté extérieur: 0; Invertir (dte/gche): no; Invertir (intérieur/extérieur): no; Forme: Rectangle; Largeur: 100.871 cm; Hauteur: 179.234 cm; Hauteur 2: 0 cm; Rayon Arc: 0 cm; Rayon Cercle: 0 cm; Demi-axe horizontal: 0 cm; Demi-axe vertical: 0 cm; IFC_Pset_Géométrie_GRILLE - décalage: 0 cm; Offset latéral: 0 cm; Décalage supérieur: 0 cm; Décalage inférieur: 0 cm; Nombre accrochages latéraux: 0; Nombre d'accrochages supérieurs: 0; Nombre accrochages inférieurs: 0; IFC_Pset_Géométrie_Niche - Présent: no; Stratigraphie: Paroi en béton armé [120,00]; Épaisseur: 12 cm; Alignement: Intérieur; Décalage: 0 cm; IFC_Pset_Système de Référence Altimétrique_INFÉRIEUR - NIVEAU: Niveau 2 (Niveau 2 13545); delta: 48.9244 cm; sous Niveau: <aucun>; IFC_Pset_Données Métré - Surface de l'Ouverture: 18100 cm2; Surface de l'Ébrasement: 6500 cm2; Surface du Seuil: 0 cm2; Surface du Seuil intérieur: 0 cm2; Volume du seuil: 0 cm3; Volume du seuil intérieur: 0 cm3; Surface de la Niche: 0 cm2; Surface de la Grille: 0 cm2; Volume de la Grille: 0 cm3
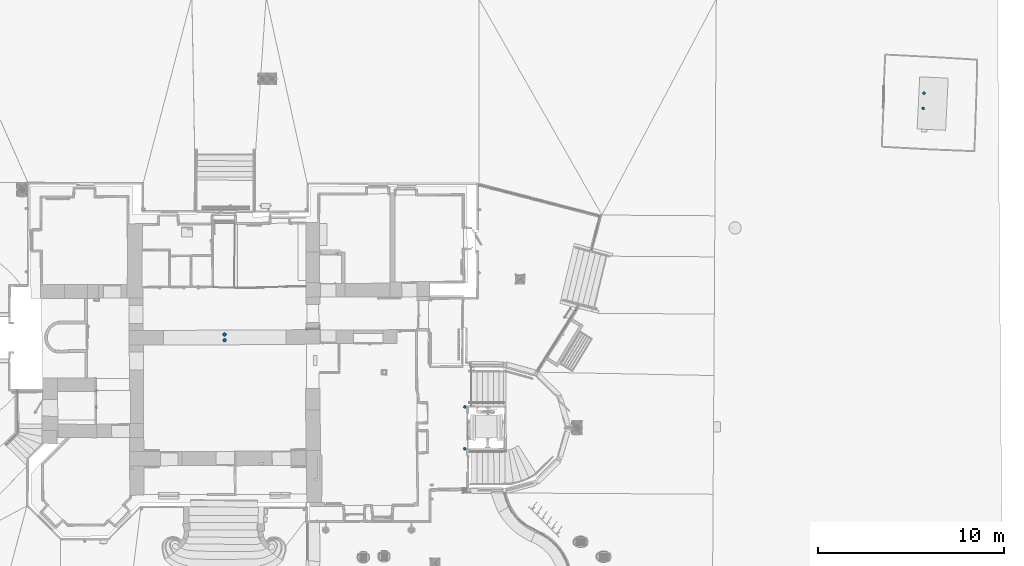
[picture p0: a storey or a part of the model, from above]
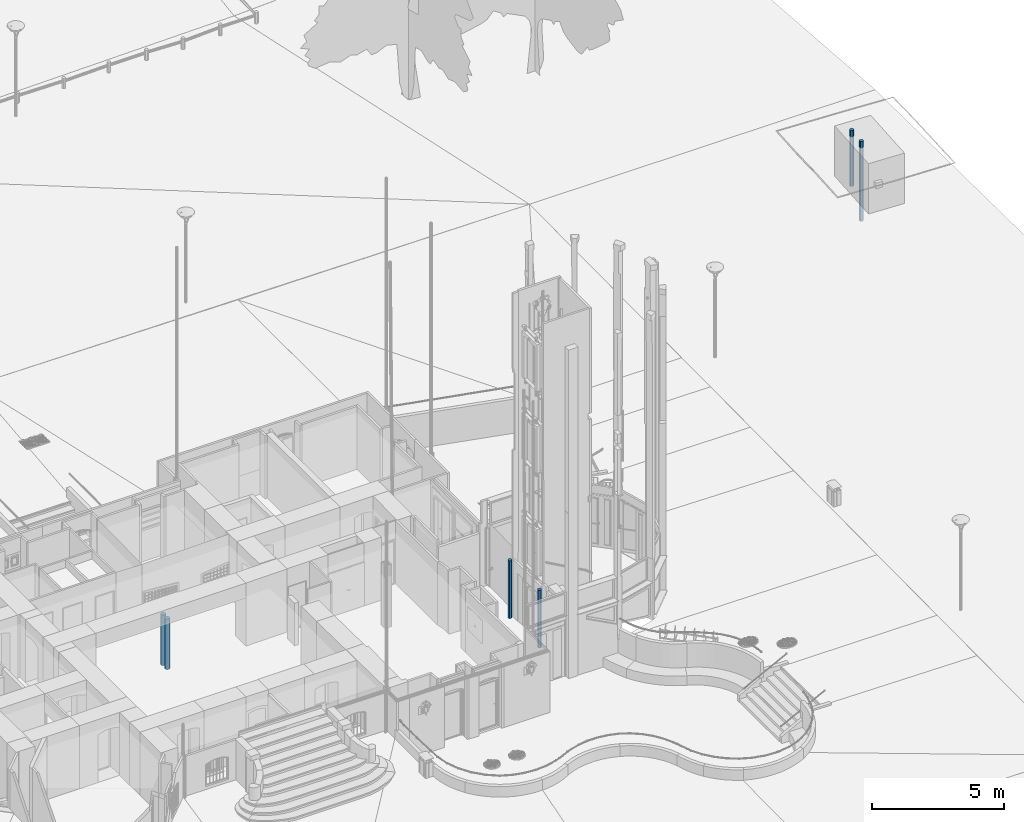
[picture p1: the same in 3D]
Properties of the parts of a building model (IFC2X3), part 15 of 37

# IfcOpeningElement: Opening (367)
Name | In | __RECOGNIZE__, ID | TPLG | TPLG_OD | GENERATE | 0, Crc
Baie 750770 | Niveau 2 | 750770 | 114 | 9006 | 1 | -746779066 | Description: _VTO_Baie; CTLG_EXTERNAL_LINK - 1, DocType: 9; 1, Tag: 211; 1, Crc: -732809594; IFC_Pset_Caractéristiques - ID: 750770; Numérotation: 156; Numéro niveau: 05; Titre niveau: Niveau 2; IFC_Pset_Géométrie_Allège - Hauteur: 0 cm; Stratigraphie: ...; Épaisseur: 0 cm; IFC_Pset_Géométrie_Ébrasement - Présent: yes; Côté supérieur: no; Côté INFÉRIEUR: no; Épaisseur extérieure: 11 cm; Épaisseur latérale gauche: 3 cm; Épaisseur latérale droite: 3 cm; Épiasseur latérale supérieure: 3 cm; Épaisseur diagonale gauche: 0 cm; Épaisseur diagonale droite: 0 cm; Épaisseur diagonale inférieure: 0 cm; Épaisseur diagonale supérieure: 0 cm; Épaisseur intérieur: 0 cm; Données: [a : 110,00; b: 30,00; c: 0,00; d: 0,00] mm; IFC_Pset_Géométrie_Seuil - Type: Aucun; Épaisseur: 0 cm; Épaisseur interne: 0 cm; Décalage séparation: 0 cm; Appui extérieur: 0 cm; Appui intérieur: 0 cm; Côté latéral externe: 0 cm; Côté latéral interne: 0 cm; IFC_Pset_Géométrie_Chambranle - Position: Aucun; Épaisseur Chambranle intérieur: 0 cm; Longueur Chambranle intérieur: 0 cm; Superposition Chambranle intérieur: 0 cm; Épaisseur Intrados: 0 cm; Épaisseur Chambranle extérieur: 0 cm; Largeur Chambranle extérieur: 0 cm; Superposition Chambranle extérieur: 0 cm; Épaisseur Intrados extérieur: 0 cm; Décalage séparation intrados: 0 cm; IFC_Pset_Géométrie_CORNICHE depuis profil - Position: Aucune; sets with these values: 2; IFC_Pset_Géométrie_CORNICHE Extérieure à partir d'un profil - Décalage: 0; Angle: 0 deg; Symétrie: no; Fermer: no; sets with these values: 2; IFC_Pset_Géométrie_BASE Extérieure à partir d'un profil - Angle: 0 deg; Symétrie: no; Côté: 0 cm; sets with these values: 2; IFC_Pset_Géométrie - Côté extérieur: 0; Invertir (dte/gche): no; Invertir (intérieur/extérieur): no; Forme: Rectangle; Largeur: 100.256 cm; Hauteur: 183.752 cm; Hauteur 2: 0 cm; Rayon Arc: 0 cm; Rayon Cercle: 0 cm; Demi-axe horizontal: 0 cm; Demi-axe vertical: 0 cm; IFC_Pset_Géométrie_GRILLE - décalage: 0 cm; Offset latéral: 0 cm; Décalage supérieur: 0 cm; Décalage inférieur: 0 cm; Nombre accrochages latéraux: 0; Nombre d'accrochages supérieurs: 0; Nombre accrochages inférieurs: 0; IFC_Pset_Géométrie_Niche - Présent: no; Stratigraphie: Paroi en béton armé [120,00]; Épaisseur: 12 cm; Alignement: Intérieur; Décalage: 0 cm; IFC_Pset_Système de Référence Altimétrique_INFÉRIEUR - NIVEAU: Niveau 2 (Niveau 2 13545); delta: 47.7056 cm; sous Niveau: <aucun>; IFC_Pset_Données Métré - Surface de l'Ouverture: 18400 cm2; Surface de l'Ébrasement: 6600 cm2; Surface du Seuil: 0 cm2; Surface du Seuil intérieur: 0 cm2; Volume du seuil: 0 cm3; Volume du seuil intérieur: 0 cm3; Surface de la Niche: 0 cm2; Surface de la Grille: 0 cm2; Volume de la Grille: 0 cm3
Baie 743474 | Niveau 2 | 743474 | 114 | 9006 | 1 | -746779066 | Description: _VTO_Baie; CTLG_EXTERNAL_LINK - 1, DocType: 9; 1, Tag: 211; 1, Crc: -732809594; IFC_Pset_Caractéristiques - ID: 743474; Numérotation: 146; Numéro niveau: 05; Titre niveau: Niveau 2; IFC_Pset_Géométrie_Allège - Hauteur: 0 cm; Stratigraphie: ...; Épaisseur: 0 cm; IFC_Pset_Géométrie_Ébrasement - Présent: yes; Côté supérieur: no; Côté INFÉRIEUR: no; Épaisseur extérieure: 11 cm; Épaisseur latérale gauche: 3 cm; Épaisseur latérale droite: 3 cm; Épiasseur latérale supérieure: 3 cm; Épaisseur diagonale gauche: 0 cm; Épaisseur diagonale droite: 0 cm; Épaisseur diagonale inférieure: 0 cm; Épaisseur diagonale supérieure: 0 cm; Épaisseur intérieur: 0 cm; Données: [a : 110,00; b: 30,00; c: 0,00; d: 0,00] mm; IFC_Pset_Géométrie_Seuil - Type: Aucun; Épaisseur: 0 cm; Épaisseur interne: 0 cm; Décalage séparation: 0 cm; Appui extérieur: 0 cm; Appui intérieur: 0 cm; Côté latéral externe: 0 cm; Côté latéral interne: 0 cm; IFC_Pset_Géométrie_Chambranle - Position: Aucun; Épaisseur Chambranle intérieur: 0 cm; Longueur Chambranle intérieur: 0 cm; Superposition Chambranle intérieur: 0 cm; Épaisseur Intrados: 0 cm; Épaisseur Chambranle extérieur: 0 cm; Largeur Chambranle extérieur: 0 cm; Superposition Chambranle extérieur: 0 cm; Épaisseur Intrados extérieur: 0 cm; Décalage séparation intrados: 0 cm; IFC_Pset_Géométrie_CORNICHE depuis profil - Position: Aucune; sets with these values: 2; IFC_Pset_Géométrie_CORNICHE Extérieure à partir d'un profil - Décalage: 0; Angle: 0 deg; Symétrie: no; Fermer: no; sets with these values: 2; IFC_Pset_Géométrie_BASE Extérieure à partir d'un profil - Angle: 0 deg; Symétrie: no; Côté: 0 cm; sets with these values: 2; IFC_Pset_Géométrie - Côté extérieur: 0; Invertir (dte/gche): no; Invertir (intérieur/extérieur): no; Forme: Rectangle; Largeur: 99.2023 cm; Hauteur: 176.513 cm; Hauteur 2: 0 cm; Rayon Arc: 0 cm; Rayon Cercle: 0 cm; Demi-axe horizontal: 0 cm; Demi-axe vertical: 0 cm; IFC_Pset_Géométrie_GRILLE - décalage: 0 cm; Offset latéral: 0 cm; Décalage supérieur: 0 cm; Décalage inférieur: 0 cm; Nombre accrochages latéraux: 0; Nombre d'accrochages supérieurs: 0; Nombre accrochages inférieurs: 0; IFC_Pset_Géométrie_Niche - Présent: no; Stratigraphie: Paroi en béton armé [120,00]; Épaisseur: 12 cm; Alignement: Intérieur; Décalage: 0 cm; IFC_Pset_Système de Référence Altimétrique_INFÉRIEUR - NIVEAU: Niveau 2 (Niveau 2 13545); delta: 49.9753 cm; sous Niveau: <aucun>; IFC_Pset_Données Métré - Surface de l'Ouverture: 17500 cm2; Surface de l'Ébrasement: 6400 cm2; Surface du Seuil: 0 cm2; Surface du Seuil intérieur: 0 cm2; Volume du seuil: 0 cm3; Volume du seuil intérieur: 0 cm3; Surface de la Niche: 0 cm2; Surface de la Grille: 0 cm2; Volume de la Grille: 0 cm3
Baie 748106 | Niveau 2 | 748106 | 114 | 9006 | 1 | -746779066 | Description: _VTO_Baie; CTLG_EXTERNAL_LINK - 1, DocType: 9; 1, Tag: 211; 1, Crc: -732809594; IFC_Pset_Caractéristiques - ID: 748106; Numérotation: 148; Numéro niveau: 05; Titre niveau: Niveau 2; IFC_Pset_Géométrie_Allège - Hauteur: 0 cm; Stratigraphie: ...; Épaisseur: 0 cm; IFC_Pset_Géométrie_Ébrasement - Présent: yes; Côté supérieur: no; Côté INFÉRIEUR: no; Épaisseur extérieure: 11 cm; Épaisseur latérale gauche: 3 cm; Épaisseur latérale droite: 3 cm; Épiasseur latérale supérieure: 3 cm; Épaisseur diagonale gauche: 0 cm; Épaisseur diagonale droite: 0 cm; Épaisseur diagonale inférieure: 0 cm; Épaisseur diagonale supérieure: 0 cm; Épaisseur intérieur: 0 cm; Données: [a : 110,00; b: 30,00; c: 0,00; d: 0,00] mm; IFC_Pset_Géométrie_Seuil - Type: Aucun; Épaisseur: 0 cm; Épaisseur interne: 0 cm; Décalage séparation: 0 cm; Appui extérieur: 0 cm; Appui intérieur: 0 cm; Côté latéral externe: 0 cm; Côté latéral interne: 0 cm; IFC_Pset_Géométrie_Chambranle - Position: Aucun; Épaisseur Chambranle intérieur: 0 cm; Longueur Chambranle intérieur: 0 cm; Superposition Chambranle intérieur: 0 cm; Épaisseur Intrados: 0 cm; Épaisseur Chambranle extérieur: 0 cm; Largeur Chambranle extérieur: 0 cm; Superposition Chambranle extérieur: 0 cm; Épaisseur Intrados extérieur: 0 cm; Décalage séparation intrados: 0 cm; IFC_Pset_Géométrie_CORNICHE depuis profil - Position: Aucune; sets with these values: 2; IFC_Pset_Géométrie_CORNICHE Extérieure à partir d'un profil - Décalage: 0; Angle: 0 deg; Symétrie: no; Fermer: no; sets with these values: 2; IFC_Pset_Géométrie_BASE Extérieure à partir d'un profil - Angle: 0 deg; Symétrie: no; Côté: 0 cm; sets with these values: 2; IFC_Pset_Géométrie - Côté extérieur: 1; Invertir (dte/gche): no; Invertir (intérieur/extérieur): yes; Forme: Rectangle; Largeur: 89.5707 cm; Hauteur: 174 cm; Hauteur 2: 0 cm; Rayon Arc: 0 cm; Rayon Cercle: 0 cm; Demi-axe horizontal: 0 cm; Demi-axe vertical: 0 cm; IFC_Pset_Géométrie_GRILLE - décalage: 0 cm; Offset latéral: 0 cm; Décalage supérieur: 0 cm; Décalage inférieur: 0 cm; Nombre accrochages latéraux: 0; Nombre d'accrochages supérieurs: 0; Nombre accrochages inférieurs: 0; IFC_Pset_Géométrie_Niche - Présent: no; Stratigraphie: Paroi en béton armé [120,00]; Épaisseur: 12 cm; Alignement: Intérieur; Décalage: 0 cm; IFC_Pset_Système de Référence Altimétrique_INFÉRIEUR - NIVEAU: Niveau 2 (Niveau 2 13545); delta: 49.0919 cm; sous Niveau: <aucun>; IFC_Pset_Données Métré - Surface de l'Ouverture: 15600 cm2; Surface de l'Ébrasement: 6300 cm2; Surface du Seuil: 0 cm2; Surface du Seuil intérieur: 0 cm2; Volume du seuil: 0 cm3; Volume du seuil intérieur: 0 cm3; Surface de la Niche: 0 cm2; Surface de la Grille: 0 cm2; Volume de la Grille: 0 cm3
Baie 748107 | Niveau 2 | 748107 | 114 | 9006 | 1 | -746779066 | Description: _VTO_Baie; CTLG_EXTERNAL_LINK - 1, DocType: 9; 1, Tag: 211; 1, Crc: -732809594; IFC_Pset_Caractéristiques - ID: 748107; Numérotation: 149; Numéro niveau: 05; Titre niveau: Niveau 2; IFC_Pset_Géométrie_Allège - Hauteur: 0 cm; Stratigraphie: ...; Épaisseur: 0 cm; IFC_Pset_Géométrie_Ébrasement - Présent: yes; Côté supérieur: no; Côté INFÉRIEUR: no; Épaisseur extérieure: 11 cm; Épaisseur latérale gauche: 3 cm; Épaisseur latérale droite: 3 cm; Épiasseur latérale supérieure: 3 cm; Épaisseur diagonale gauche: 0 cm; Épaisseur diagonale droite: 0 cm; Épaisseur diagonale inférieure: 0 cm; Épaisseur diagonale supérieure: 0 cm; Épaisseur intérieur: 0 cm; Données: [a : 110,00; b: 30,00; c: 0,00; d: 0,00] mm; IFC_Pset_Géométrie_Seuil - Type: Aucun; Épaisseur: 0 cm; Épaisseur interne: 0 cm; Décalage séparation: 0 cm; Appui extérieur: 0 cm; Appui intérieur: 0 cm; Côté latéral externe: 0 cm; Côté latéral interne: 0 cm; IFC_Pset_Géométrie_Chambranle - Position: Aucun; Épaisseur Chambranle intérieur: 0 cm; Longueur Chambranle intérieur: 0 cm; Superposition Chambranle intérieur: 0 cm; Épaisseur Intrados: 0 cm; Épaisseur Chambranle extérieur: 0 cm; Largeur Chambranle extérieur: 0 cm; Superposition Chambranle extérieur: 0 cm; Épaisseur Intrados extérieur: 0 cm; Décalage séparation intrados: 0 cm; IFC_Pset_Géométrie_CORNICHE depuis profil - Position: Aucune; sets with these values: 2; IFC_Pset_Géométrie_CORNICHE Extérieure à partir d'un profil - Décalage: 0; Angle: 0 deg; Symétrie: no; Fermer: no; sets with these values: 2; IFC_Pset_Géométrie_BASE Extérieure à partir d'un profil - Angle: 0 deg; Symétrie: no; Côté: 0 cm; sets with these values: 2; IFC_Pset_Géométrie - Côté extérieur: 1; Invertir (dte/gche): no; Invertir (intérieur/extérieur): yes; Forme: Rectangle; Largeur: 89.5561 cm; Hauteur: 174.154 cm; Hauteur 2: 0 cm; Rayon Arc: 0 cm; Rayon Cercle: 0 cm; Demi-axe horizontal: 0 cm; Demi-axe vertical: 0 cm; IFC_Pset_Géométrie_GRILLE - décalage: 0 cm; Offset latéral: 0 cm; Décalage supérieur: 0 cm; Décalage inférieur: 0 cm; Nombre accrochages latéraux: 0; Nombre d'accrochages supérieurs: 0; Nombre accrochages inférieurs: 0; IFC_Pset_Géométrie_Niche - Présent: no; Stratigraphie: Paroi en béton armé [120,00]; Épaisseur: 12 cm; Alignement: Intérieur; Décalage: 0 cm; IFC_Pset_Système de Référence Altimétrique_INFÉRIEUR - NIVEAU: Niveau 2 (Niveau 2 13545); delta: 49.8897 cm; sous Niveau: <aucun>; IFC_Pset_Données Métré - Surface de l'Ouverture: 15600 cm2; Surface de l'Ébrasement: 6300 cm2; Surface du Seuil: 0 cm2; Surface du Seuil intérieur: 0 cm2; Volume du seuil: 0 cm3; Volume du seuil intérieur: 0 cm3; Surface de la Niche: 0 cm2; Surface de la Grille: 0 cm2; Volume de la Grille: 0 cm3
Baie 734179 | Niveau 2 | 734179 | 114 | 9006 | 1 | -746779066 | Description: _VTO_Baie; CTLG_EXTERNAL_LINK - 1, DocType: 9; 1, Tag: 211; 1, Crc: -732809594; IFC_Pset_Caractéristiques - ID: 734179; Numérotation: 137; Numéro niveau: 05; Titre niveau: Niveau 2; IFC_Pset_Géométrie_Allège - Hauteur: 0 cm; Stratigraphie: ...; Épaisseur: 0 cm; IFC_Pset_Géométrie_Ébrasement - Présent: yes; Côté supérieur: no; Côté INFÉRIEUR: no; Épaisseur extérieure: 10.5 cm; Épaisseur latérale gauche: 3 cm; Épaisseur latérale droite: 3 cm; Épiasseur latérale supérieure: 3 cm; Épaisseur diagonale gauche: 0 cm; Épaisseur diagonale droite: 0 cm; Épaisseur diagonale inférieure: 0 cm; Épaisseur diagonale supérieure: 0 cm; Épaisseur intérieur: 0 cm; Données: [a : 105,00; b: 30,00; c: 0,00; d: 0,00] mm; IFC_Pset_Géométrie_Seuil - Type: Aucun; Épaisseur: 0 cm; Épaisseur interne: 0 cm; Décalage séparation: 0 cm; Appui extérieur: 0 cm; Appui intérieur: 0 cm; Côté latéral externe: 0 cm; Côté latéral interne: 0 cm; IFC_Pset_Géométrie_Chambranle - Position: Aucun; Épaisseur Chambranle intérieur: 0 cm; Longueur Chambranle intérieur: 0 cm; Superposition Chambranle intérieur: 0 cm; Épaisseur Intrados: 0 cm; Épaisseur Chambranle extérieur: 0 cm; Largeur Chambranle extérieur: 0 cm; Superposition Chambranle extérieur: 0 cm; Épaisseur Intrados extérieur: 0 cm; Décalage séparation intrados: 0 cm; IFC_Pset_Géométrie_CORNICHE depuis profil - Position: Aucune; sets with these values: 2; IFC_Pset_Géométrie_CORNICHE Extérieure à partir d'un profil - Décalage: 0; Angle: 0 deg; Symétrie: no; Fermer: no; sets with these values: 2; IFC_Pset_Géométrie_BASE Extérieure à partir d'un profil - Angle: 0 deg; Symétrie: no; Côté: 0 cm; sets with these values: 2; IFC_Pset_Géométrie - Côté extérieur: 0; Invertir (dte/gche): no; Invertir (intérieur/extérieur): no; Forme: Rectangle; Largeur: 99.7678 cm; Hauteur: 179.468 cm; Hauteur 2: 0 cm; Rayon Arc: 0 cm; Rayon Cercle: 0 cm; Demi-axe horizontal: 0 cm; Demi-axe vertical: 0 cm; IFC_Pset_Géométrie_GRILLE - décalage: 0 cm; Offset latéral: 0 cm; Décalage supérieur: 0 cm; Décalage inférieur: 0 cm; Nombre accrochages latéraux: 0; Nombre d'accrochages supérieurs: 0; Nombre accrochages inférieurs: 0; IFC_Pset_Géométrie_Niche - Présent: no; Stratigraphie: Paroi en béton armé [120,00]; Épaisseur: 12 cm; Alignement: Intérieur; Décalage: 0 cm; IFC_Pset_Système de Référence Altimétrique_INFÉRIEUR - NIVEAU: Niveau 2 (Niveau 2 13545); delta: 48.3849 cm; sous Niveau: <aucun>; IFC_Pset_Données Métré - Surface de l'Ouverture: 17900 cm2; Surface de l'Ébrasement: 6500 cm2; Surface du Seuil: 0 cm2; Surface du Seuil intérieur: 0 cm2; Volume du seuil: 0 cm3; Volume du seuil intérieur: 0 cm3; Surface de la Niche: 0 cm2; Surface de la Grille: 0 cm2; Volume de la Grille: 0 cm3
4294966440_11 | Niveau 2 | -856 | 2002 | 2002 | 0 | -1292786862
4294966535_11 | Niveau 2 | -761 | 2002 | 2002 | 0 | -1292786862
4294966495_11 | Niveau 2 | -801 | 2002 | 2002 | 0 | -1292786862
4294966491_11 | Niveau 2 | -805 | 2002 | 2002 | 0 | -1292786862
4294966490_11 | Niveau 2 | -806 | 2002 | 2002 | 0 | -1292786862
4294966492_11 | Niveau 2 | -804 | 2002 | 2002 | 0 | -1292786862
4294966493_11 | Niveau 2 | -803 | 2002 | 2002 | 0 | -1292786862
4294966494_11 | Niveau 2 | -802 | 2002 | 2002 | 0 | -1292786862
4294966489_11 | Niveau 2 | -807 | 2002 | 2002 | 0 | -1292786862
4294966488_11 | Niveau 2 | -808 | 2002 | 2002 | 0 | -1292786862
4294966433_11 | Niveau 2 | -863 | 2002 | 2002 | 0 | -1292786862
4294966446_11 | Niveau 2 | -850 | 2002 | 2002 | 0 | -1292786862
Baie 745940 | Niveau 2 | 745940 | 114 | 9006 | 1 | -746779066 | Description: _VTO_Baie; CTLG_EXTERNAL_LINK - 1, DocType: 9; 1, Tag: 211; 1, Crc: -732809594; IFC_Pset_Caractéristiques - ID: 745940; Numérotation: 147; Numéro niveau: 05; Titre niveau: Niveau 2; IFC_Pset_Géométrie_Allège - Hauteur: 0 cm; Stratigraphie: ...; Épaisseur: 0 cm; IFC_Pset_Géométrie_Ébrasement - Présent: yes; Côté supérieur: no; Côté INFÉRIEUR: no; Épaisseur extérieure: 11 cm; Épaisseur latérale gauche: 3 cm; Épaisseur latérale droite: 3 cm; Épiasseur latérale supérieure: 3 cm; Épaisseur diagonale gauche: 0 cm; Épaisseur diagonale droite: 0 cm; Épaisseur diagonale inférieure: 0 cm; Épaisseur diagonale supérieure: 0 cm; Épaisseur intérieur: 0 cm; Données: [a : 110,00; b: 30,00; c: 0,00; d: 0,00] mm; IFC_Pset_Géométrie_Seuil - Type: Aucun; Épaisseur: 0 cm; Épaisseur interne: 0 cm; Décalage séparation: 0 cm; Appui extérieur: 0 cm; Appui intérieur: 0 cm; Côté latéral externe: 0 cm; Côté latéral interne: 0 cm; IFC_Pset_Géométrie_Chambranle - Position: Aucun; Épaisseur Chambranle intérieur: 0 cm; Longueur Chambranle intérieur: 0 cm; Superposition Chambranle intérieur: 0 cm; Épaisseur Intrados: 0 cm; Épaisseur Chambranle extérieur: 0 cm; Largeur Chambranle extérieur: 0 cm; Superposition Chambranle extérieur: 0 cm; Épaisseur Intrados extérieur: 0 cm; Décalage séparation intrados: 0 cm; IFC_Pset_Géométrie_CORNICHE depuis profil - Position: Aucune; sets with these values: 2; IFC_Pset_Géométrie_CORNICHE Extérieure à partir d'un profil - Décalage: 0; Angle: 0 deg; Symétrie: no; Fermer: no; sets with these values: 2; IFC_Pset_Géométrie_BASE Extérieure à partir d'un profil - Angle: 0 deg; Symétrie: no; Côté: 0 cm; sets with these values: 2; IFC_Pset_Géométrie - Côté extérieur: 1; Invertir (dte/gche): no; Invertir (intérieur/extérieur): yes; Forme: Rectangle; Largeur: 99.6884 cm; Hauteur: 185.191 cm; Hauteur 2: 0 cm; Rayon Arc: 0 cm; Rayon Cercle: 0 cm; Demi-axe horizontal: 0 cm; Demi-axe vertical: 0 cm; IFC_Pset_Géométrie_GRILLE - décalage: 0 cm; Offset latéral: 0 cm; Décalage supérieur: 0 cm; Décalage inférieur: 0 cm; Nombre accrochages latéraux: 0; Nombre d'accrochages supérieurs: 0; Nombre accrochages inférieurs: 0; IFC_Pset_Géométrie_Niche - Présent: no; Stratigraphie: Paroi en béton armé [120,00]; Épaisseur: 12 cm; Alignement: Intérieur; Décalage: 0 cm; IFC_Pset_Système de Référence Altimétrique_INFÉRIEUR - NIVEAU: Niveau 2 (Niveau 2 13545); delta: 48.6954 cm; sous Niveau: <aucun>; IFC_Pset_Données Métré - Surface de l'Ouverture: 18500 cm2; Surface de l'Ébrasement: 6700 cm2; Surface du Seuil: 0 cm2; Surface du Seuil intérieur: 0 cm2; Volume du seuil: 0 cm3; Volume du seuil intérieur: 0 cm3; Surface de la Niche: 0 cm2; Surface de la Grille: 0 cm2; Volume de la Grille: 0 cm3
Baie 740524 | Niveau 2 | 740524 | 114 | 9006 | 1 | -746779066 | Description: _VTO_Baie; CTLG_EXTERNAL_LINK - 1, DocType: 9; 1, Tag: 211; 1, Crc: -732809594; IFC_Pset_Caractéristiques - ID: 740524; Numérotation: 143; Numéro niveau: 05; Titre niveau: Niveau 2; IFC_Pset_Géométrie_Allège - Hauteur: 0 cm; Stratigraphie: ...; Épaisseur: 0 cm; IFC_Pset_Géométrie_Ébrasement - Présent: yes; Côté supérieur: no; Côté INFÉRIEUR: no; Épaisseur extérieure: 10 cm; Épaisseur latérale gauche: 3 cm; Épaisseur latérale droite: 3 cm; Épiasseur latérale supérieure: 3 cm; Épaisseur diagonale gauche: 0 cm; Épaisseur diagonale droite: 0 cm; Épaisseur diagonale inférieure: 0 cm; Épaisseur diagonale supérieure: 0 cm; Épaisseur intérieur: 0 cm; Données: [a : 100,00; b: 30,00; c: 0,00; d: 0,00] mm; IFC_Pset_Géométrie_Seuil - Type: Aucun; Épaisseur: 0 cm; Épaisseur interne: 0 cm; Décalage séparation: 0 cm; Appui extérieur: 0 cm; Appui intérieur: 0 cm; Côté latéral externe: 0 cm; Côté latéral interne: 0 cm; IFC_Pset_Géométrie_Chambranle - Position: Aucun; Épaisseur Chambranle intérieur: 0 cm; Longueur Chambranle intérieur: 0 cm; Superposition Chambranle intérieur: 0 cm; Épaisseur Intrados: 0 cm; Épaisseur Chambranle extérieur: 0 cm; Largeur Chambranle extérieur: 0 cm; Superposition Chambranle extérieur: 0 cm; Épaisseur Intrados extérieur: 0 cm; Décalage séparation intrados: 0 cm; IFC_Pset_Géométrie_CORNICHE depuis profil - Position: Aucune; sets with these values: 2; IFC_Pset_Géométrie_CORNICHE Extérieure à partir d'un profil - Décalage: 0; Angle: 0 deg; Symétrie: no; Fermer: no; sets with these values: 2; IFC_Pset_Géométrie_BASE Extérieure à partir d'un profil - Angle: 0 deg; Symétrie: no; Côté: 0 cm; sets with these values: 2; IFC_Pset_Géométrie - Côté extérieur: 0; Invertir (dte/gche): no; Invertir (intérieur/extérieur): no; Forme: Rectangle; Largeur: 69.4054 cm; Hauteur: 175.478 cm; Hauteur 2: 0 cm; Rayon Arc: 0 cm; Rayon Cercle: 0 cm; Demi-axe horizontal: 0 cm; Demi-axe vertical: 0 cm; IFC_Pset_Géométrie_GRILLE - décalage: 0 cm; Offset latéral: 0 cm; Décalage supérieur: 0 cm; Décalage inférieur: 0 cm; Nombre accrochages latéraux: 0; Nombre d'accrochages supérieurs: 0; Nombre accrochages inférieurs: 0; IFC_Pset_Géométrie_Niche - Présent: no; Stratigraphie: Paroi en béton armé [120,00]; Épaisseur: 12 cm; Alignement: Intérieur; Décalage: 0 cm; IFC_Pset_Système de Référence Altimétrique_INFÉRIEUR - NIVEAU: Niveau 2 (Niveau 2 13545); delta: 50 cm; sous Niveau: <aucun>; IFC_Pset_Données Métré - Surface de l'Ouverture: 12200 cm2; Surface de l'Ébrasement: 6000 cm2; Surface du Seuil: 0 cm2; Surface du Seuil intérieur: 0 cm2; Volume du seuil: 0 cm3; Volume du seuil intérieur: 0 cm3; Surface de la Niche: 0 cm2; Surface de la Grille: 0 cm2; Volume de la Grille: 0 cm3
Baie 740523 | Niveau 2 | 740523 | 114 | 9006 | 1 | -746779066 | Description: _VTO_Baie; CTLG_EXTERNAL_LINK - 1, DocType: 9; 1, Tag: 211; 1, Crc: -732809594; IFC_Pset_Caractéristiques - ID: 740523; Numérotation: 142; Numéro niveau: 05; Titre niveau: Niveau 2; IFC_Pset_Géométrie_Allège - Hauteur: 0 cm; Stratigraphie: ...; Épaisseur: 0 cm; IFC_Pset_Géométrie_Ébrasement - Présent: yes; Côté supérieur: no; Côté INFÉRIEUR: no; Épaisseur extérieure: 10 cm; Épaisseur latérale gauche: 3 cm; Épaisseur latérale droite: 3 cm; Épiasseur latérale supérieure: 3 cm; Épaisseur diagonale gauche: 0 cm; Épaisseur diagonale droite: 0 cm; Épaisseur diagonale inférieure: 0 cm; Épaisseur diagonale supérieure: 0 cm; Épaisseur intérieur: 0 cm; Données: [a : 100,00; b: 30,00; c: 0,00; d: 0,00] mm; IFC_Pset_Géométrie_Seuil - Type: Aucun; Épaisseur: 0 cm; Épaisseur interne: 0 cm; Décalage séparation: 0 cm; Appui extérieur: 0 cm; Appui intérieur: 0 cm; Côté latéral externe: 0 cm; Côté latéral interne: 0 cm; IFC_Pset_Géométrie_Chambranle - Position: Aucun; Épaisseur Chambranle intérieur: 0 cm; Longueur Chambranle intérieur: 0 cm; Superposition Chambranle intérieur: 0 cm; Épaisseur Intrados: 0 cm; Épaisseur Chambranle extérieur: 0 cm; Largeur Chambranle extérieur: 0 cm; Superposition Chambranle extérieur: 0 cm; Épaisseur Intrados extérieur: 0 cm; Décalage séparation intrados: 0 cm; IFC_Pset_Géométrie_CORNICHE depuis profil - Position: Aucune; sets with these values: 2; IFC_Pset_Géométrie_CORNICHE Extérieure à partir d'un profil - Décalage: 0; Angle: 0 deg; Symétrie: no; Fermer: no; sets with these values: 2; IFC_Pset_Géométrie_BASE Extérieure à partir d'un profil - Angle: 0 deg; Symétrie: no; Côté: 0 cm; sets with these values: 2; IFC_Pset_Géométrie - Côté extérieur: 0; Invertir (dte/gche): no; Invertir (intérieur/extérieur): no; Forme: Rectangle; Largeur: 69.3902 cm; Hauteur: 174.92 cm; Hauteur 2: 0 cm; Rayon Arc: 0 cm; Rayon Cercle: 0 cm; Demi-axe horizontal: 0 cm; Demi-axe vertical: 0 cm; IFC_Pset_Géométrie_GRILLE - décalage: 0 cm; Offset latéral: 0 cm; Décalage supérieur: 0 cm; Décalage inférieur: 0 cm; Nombre accrochages latéraux: 0; Nombre d'accrochages supérieurs: 0; Nombre accrochages inférieurs: 0; IFC_Pset_Géométrie_Niche - Présent: no; Stratigraphie: Paroi en béton armé [120,00]; Épaisseur: 12 cm; Alignement: Intérieur; Décalage: 0 cm; IFC_Pset_Système de Référence Altimétrique_INFÉRIEUR - NIVEAU: Niveau 2 (Niveau 2 13545); delta: 50 cm; sous Niveau: <aucun>; IFC_Pset_Données Métré - Surface de l'Ouverture: 12100 cm2; Surface de l'Ébrasement: 5900 cm2; Surface du Seuil: 0 cm2; Surface du Seuil intérieur: 0 cm2; Volume du seuil: 0 cm3; Volume du seuil intérieur: 0 cm3; Surface de la Niche: 0 cm2; Surface de la Grille: 0 cm2; Volume de la Grille: 0 cm3
Baie 741210 | Niveau 2 | 741210 | 114 | 9006 | 1 | -746779066 | Description: _VTO_Baie; CTLG_EXTERNAL_LINK - 1, DocType: 9; 1, Tag: 211; 1, Crc: -732809594; IFC_Pset_Caractéristiques - ID: 741210; Numérotation: 144; Numéro niveau: 05; Titre niveau: Niveau 2; IFC_Pset_Géométrie_Allège - Hauteur: 0 cm; Stratigraphie: ...; Épaisseur: 0 cm; IFC_Pset_Géométrie_Ébrasement - Présent: yes; Côté supérieur: no; Côté INFÉRIEUR: no; Épaisseur extérieure: 10 cm; Épaisseur latérale gauche: 3 cm; Épaisseur latérale droite: 3 cm; Épiasseur latérale supérieure: 3 cm; Épaisseur diagonale gauche: 0 cm; Épaisseur diagonale droite: 0 cm; Épaisseur diagonale inférieure: 0 cm; Épaisseur diagonale supérieure: 0 cm; Épaisseur intérieur: 0 cm; Données: [a : 100,00; b: 30,00; c: 0,00; d: 0,00] mm; IFC_Pset_Géométrie_Seuil - Type: Aucun; Épaisseur: 0 cm; Épaisseur interne: 0 cm; Décalage séparation: 0 cm; Appui extérieur: 0 cm; Appui intérieur: 0 cm; Côté latéral externe: 0 cm; Côté latéral interne: 0 cm; IFC_Pset_Géométrie_Chambranle - Position: Aucun; Épaisseur Chambranle intérieur: 0 cm; Longueur Chambranle intérieur: 0 cm; Superposition Chambranle intérieur: 0 cm; Épaisseur Intrados: 0 cm; Épaisseur Chambranle extérieur: 0 cm; Largeur Chambranle extérieur: 0 cm; Superposition Chambranle extérieur: 0 cm; Épaisseur Intrados extérieur: 0 cm; Décalage séparation intrados: 0 cm; IFC_Pset_Géométrie_CORNICHE depuis profil - Position: Aucune; sets with these values: 2; IFC_Pset_Géométrie_CORNICHE Extérieure à partir d'un profil - Décalage: 0; Angle: 0 deg; Symétrie: no; Fermer: no; sets with these values: 2; IFC_Pset_Géométrie_BASE Extérieure à partir d'un profil - Angle: 0 deg; Symétrie: no; Côté: 0 cm; sets with these values: 2; IFC_Pset_Géométrie - Côté extérieur: 0; Invertir (dte/gche): no; Invertir (intérieur/extérieur): no; Forme: Rectangle; Largeur: 39.5994 cm; Hauteur: 119.679 cm; Hauteur 2: 0 cm; Rayon Arc: 0 cm; Rayon Cercle: 0 cm; Demi-axe horizontal: 0 cm; Demi-axe vertical: 0 cm; IFC_Pset_Géométrie_GRILLE - décalage: 0 cm; Offset latéral: 0 cm; Décalage supérieur: 0 cm; Décalage inférieur: 0 cm; Nombre accrochages latéraux: 0; Nombre d'accrochages supérieurs: 0; Nombre accrochages inférieurs: 0; IFC_Pset_Géométrie_Niche - Présent: no; Stratigraphie: Paroi en béton armé [120,00]; Épaisseur: 12 cm; Alignement: Intérieur; Décalage: 0 cm; IFC_Pset_Système de Référence Altimétrique_INFÉRIEUR - NIVEAU: Niveau 2 (Niveau 2 13545); delta: 52 cm; sous Niveau: <aucun>; IFC_Pset_Données Métré - Surface de l'Ouverture: 4700 cm2; Surface de l'Ébrasement: 4100 cm2; Surface du Seuil: 0 cm2; Surface du Seuil intérieur: 0 cm2; Volume du seuil: 0 cm3; Volume du seuil intérieur: 0 cm3; Surface de la Niche: 0 cm2; Surface de la Grille: 0 cm2; Volume de la Grille: 0 cm3
Baie 741212 | Niveau 2 | 741212 | 114 | 9006 | 1 | -746779066 | Description: _VTO_Baie; CTLG_EXTERNAL_LINK - 1, DocType: 9; 1, Tag: 211; 1, Crc: -732809594; IFC_Pset_Caractéristiques - ID: 741212; Numérotation: 145; Numéro niveau: 05; Titre niveau: Niveau 2; IFC_Pset_Géométrie_Allège - Hauteur: 0 cm; Stratigraphie: ...; Épaisseur: 0 cm; IFC_Pset_Géométrie_Ébrasement - Présent: yes; Côté supérieur: no; Côté INFÉRIEUR: no; Épaisseur extérieure: 10 cm; Épaisseur latérale gauche: 3 cm; Épaisseur latérale droite: 3 cm; Épiasseur latérale supérieure: 3 cm; Épaisseur diagonale gauche: 0 cm; Épaisseur diagonale droite: 0 cm; Épaisseur diagonale inférieure: 0 cm; Épaisseur diagonale supérieure: 0 cm; Épaisseur intérieur: 0 cm; Données: [a : 100,00; b: 30,00; c: 0,00; d: 0,00] mm; IFC_Pset_Géométrie_Seuil - Type: Aucun; Épaisseur: 0 cm; Épaisseur interne: 0 cm; Décalage séparation: 0 cm; Appui extérieur: 0 cm; Appui intérieur: 0 cm; Côté latéral externe: 0 cm; Côté latéral interne: 0 cm; IFC_Pset_Géométrie_Chambranle - Position: Aucun; Épaisseur Chambranle intérieur: 0 cm; Longueur Chambranle intérieur: 0 cm; Superposition Chambranle intérieur: 0 cm; Épaisseur Intrados: 0 cm; Épaisseur Chambranle extérieur: 0 cm; Largeur Chambranle extérieur: 0 cm; Superposition Chambranle extérieur: 0 cm; Épaisseur Intrados extérieur: 0 cm; Décalage séparation intrados: 0 cm; IFC_Pset_Géométrie_CORNICHE depuis profil - Position: Aucune; sets with these values: 2; IFC_Pset_Géométrie_CORNICHE Extérieure à partir d'un profil - Décalage: 0; Angle: 0 deg; Symétrie: no; Fermer: no; sets with these values: 2; IFC_Pset_Géométrie_BASE Extérieure à partir d'un profil - Angle: 0 deg; Symétrie: no; Côté: 0 cm; sets with these values: 2; IFC_Pset_Géométrie - Côté extérieur: 0; Invertir (dte/gche): no; Invertir (intérieur/extérieur): no; Forme: Rectangle; Largeur: 39.5994 cm; Hauteur: 115 cm; Hauteur 2: 0 cm; Rayon Arc: 0 cm; Rayon Cercle: 0 cm; Demi-axe horizontal: 0 cm; Demi-axe vertical: 0 cm; IFC_Pset_Géométrie_GRILLE - décalage: 0 cm; Offset latéral: 0 cm; Décalage supérieur: 0 cm; Décalage inférieur: 0 cm; Nombre accrochages latéraux: 0; Nombre d'accrochages supérieurs: 0; Nombre accrochages inférieurs: 0; IFC_Pset_Géométrie_Niche - Présent: no; Stratigraphie: Paroi en béton armé [120,00]; Épaisseur: 12 cm; Alignement: Intérieur; Décalage: 0 cm; IFC_Pset_Système de Référence Altimétrique_INFÉRIEUR - NIVEAU: Niveau 2 (Niveau 2 13545); delta: 54 cm; sous Niveau: <aucun>; IFC_Pset_Données Métré - Surface de l'Ouverture: 4600 cm2; Surface de l'Ébrasement: 3900 cm2; Surface du Seuil: 0 cm2; Surface du Seuil intérieur: 0 cm2; Volume du seuil: 0 cm3; Volume du seuil intérieur: 0 cm3; Surface de la Niche: 0 cm2; Surface de la Grille: 0 cm2; Volume de la Grille: 0 cm3
Baie 750236 | Niveau 2 | 750236 | 114 | 9006 | 1 | -746779066 | Description: _VTO_Baie; CTLG_EXTERNAL_LINK - 1, DocType: 9; 1, Tag: 211; 1, Crc: -732809594; IFC_Pset_Caractéristiques - ID: 750236; Numérotation: 153; Numéro niveau: 05; Titre niveau: Niveau 2; IFC_Pset_Géométrie_Allège - Hauteur: 0 cm; Stratigraphie: ...; Épaisseur: 0 cm; IFC_Pset_Géométrie_Ébrasement - Présent: yes; Côté supérieur: no; Côté INFÉRIEUR: no; Épaisseur extérieure: 11 cm; Épaisseur latérale gauche: 3 cm; Épaisseur latérale droite: 3 cm; Épiasseur latérale supérieure: 3 cm; Épaisseur diagonale gauche: 0 cm; Épaisseur diagonale droite: 0 cm; Épaisseur diagonale inférieure: 0 cm; Épaisseur diagonale supérieure: 0 cm; Épaisseur intérieur: 0 cm; Données: [a : 110,00; b: 30,00; c: 0,00; d: 0,00] mm; IFC_Pset_Géométrie_Seuil - Type: Aucun; Épaisseur: 0 cm; Épaisseur interne: 0 cm; Décalage séparation: 0 cm; Appui extérieur: 0 cm; Appui intérieur: 0 cm; Côté latéral externe: 0 cm; Côté latéral interne: 0 cm; IFC_Pset_Géométrie_Chambranle - Position: Aucun; Épaisseur Chambranle intérieur: 0 cm; Longueur Chambranle intérieur: 0 cm; Superposition Chambranle intérieur: 0 cm; Épaisseur Intrados: 0 cm; Épaisseur Chambranle extérieur: 0 cm; Largeur Chambranle extérieur: 0 cm; Superposition Chambranle extérieur: 0 cm; Épaisseur Intrados extérieur: 0 cm; Décalage séparation intrados: 0 cm; IFC_Pset_Géométrie_CORNICHE depuis profil - Position: Aucune; sets with these values: 2; IFC_Pset_Géométrie_CORNICHE Extérieure à partir d'un profil - Décalage: 0; Angle: 0 deg; Symétrie: no; Fermer: no; sets with these values: 2; IFC_Pset_Géométrie_BASE Extérieure à partir d'un profil - Angle: 0 deg; Symétrie: no; Côté: 0 cm; sets with these values: 2; IFC_Pset_Géométrie - Côté extérieur: 1; Invertir (dte/gche): no; Invertir (intérieur/extérieur): yes; Forme: Rectangle; Largeur: 39.5994 cm; Hauteur: 100 cm; Hauteur 2: 0 cm; Rayon Arc: 0 cm; Rayon Cercle: 0 cm; Demi-axe horizontal: 0 cm; Demi-axe vertical: 0 cm; IFC_Pset_Géométrie_GRILLE - décalage: 0 cm; Offset latéral: 0 cm; Décalage supérieur: 0 cm; Décalage inférieur: 0 cm; Nombre accrochages latéraux: 0; Nombre d'accrochages supérieurs: 0; Nombre accrochages inférieurs: 0; IFC_Pset_Géométrie_Niche - Présent: no; Stratigraphie: Paroi en béton armé [120,00]; Épaisseur: 12 cm; Alignement: Intérieur; Décalage: 0 cm; IFC_Pset_Système de Référence Altimétrique_INFÉRIEUR - NIVEAU: Niveau 2 (Niveau 2 13545); delta: 91.6 cm; sous Niveau: <aucun>; IFC_Pset_Données Métré - Surface de l'Ouverture: 4000 cm2; Surface de l'Ébrasement: 3600 cm2; Surface du Seuil: 0 cm2; Surface du Seuil intérieur: 0 cm2; Volume du seuil: 0 cm3; Volume du seuil intérieur: 0 cm3; Surface de la Niche: 0 cm2; Surface de la Grille: 0 cm2; Volume de la Grille: 0 cm3
Baie 1905136 | Niveau 2 | 1905136 | 114 | 9006 | 1 | -746779066 | Description: _VTO_Baie; CTLG_EXTERNAL_LINK - 1, DocType: 9; 1, Tag: 211; 1, Crc: -732809594; IFC_Pset_Caractéristiques - ID: 1905136; Numérotation: 171; Numéro niveau: 05; Titre niveau: Niveau 2; IFC_Pset_Géométrie_Allège - Hauteur: 0 cm; Stratigraphie: ...; Épaisseur: 0 cm; IFC_Pset_Géométrie_Ébrasement - Présent: yes; Côté supérieur: no; Côté INFÉRIEUR: no; Épaisseur extérieure: 11 cm; Épaisseur latérale gauche: 3 cm; Épaisseur latérale droite: 3 cm; Épiasseur latérale supérieure: 3 cm; Épaisseur diagonale gauche: 0 cm; Épaisseur diagonale droite: 0 cm; Épaisseur diagonale inférieure: 0 cm; Épaisseur diagonale supérieure: 0 cm; Épaisseur intérieur: 0 cm; Données: [a : 110,00; b: 30,00; c: 0,00; d: 0,00] mm; IFC_Pset_Géométrie_Seuil - Type: Aucun; Épaisseur: 0 cm; Épaisseur interne: 0 cm; Décalage séparation: 0 cm; Appui extérieur: 0 cm; Appui intérieur: 0 cm; Côté latéral externe: 0 cm; Côté latéral interne: 0 cm; IFC_Pset_Géométrie_Chambranle - Position: Aucun; Épaisseur Chambranle intérieur: 0 cm; Longueur Chambranle intérieur: 0 cm; Superposition Chambranle intérieur: 0 cm; Épaisseur Intrados: 0 cm; Épaisseur Chambranle extérieur: 0 cm; Largeur Chambranle extérieur: 0 cm; Superposition Chambranle extérieur: 0 cm; Épaisseur Intrados extérieur: 0 cm; Décalage séparation intrados: 0 cm; IFC_Pset_Géométrie_CORNICHE depuis profil - Position: Aucune; sets with these values: 2; IFC_Pset_Géométrie_CORNICHE Extérieure à partir d'un profil - Décalage: 0; Angle: 0 deg; Symétrie: no; Fermer: no; sets with these values: 2; IFC_Pset_Géométrie_BASE Extérieure à partir d'un profil - Angle: 0 deg; Symétrie: no; Côté: 0 cm; sets with these values: 2; IFC_Pset_Géométrie - Côté extérieur: 1; Invertir (dte/gche): no; Invertir (intérieur/extérieur): yes; Forme: Rectangle; Largeur: 98.567 cm; Hauteur: 136.089 cm; Hauteur 2: 0 cm; Rayon Arc: 0 cm; Rayon Cercle: 0 cm; Demi-axe horizontal: 0 cm; Demi-axe vertical: 0 cm; IFC_Pset_Géométrie_GRILLE - décalage: 0 cm; Offset latéral: 0 cm; Décalage supérieur: 0 cm; Décalage inférieur: 0 cm; Nombre accrochages latéraux: 0; Nombre d'accrochages supérieurs: 0; Nombre accrochages inférieurs: 0; IFC_Pset_Géométrie_Niche - Présent: no; Stratigraphie: Paroi en béton armé [120,00]; Épaisseur: 12 cm; Alignement: Intérieur; Décalage: 0 cm; IFC_Pset_Système de Référence Altimétrique_INFÉRIEUR - NIVEAU: Niveau 2 (Niveau 2 13545); delta: 91.6 cm; sous Niveau: <aucun>; IFC_Pset_Données Métré - Surface de l'Ouverture: 13400 cm2; Surface de l'Ébrasement: 4900 cm2; Surface du Seuil: 0 cm2; Surface du Seuil intérieur: 0 cm2; Volume du seuil: 0 cm3; Volume du seuil intérieur: 0 cm3; Surface de la Niche: 0 cm2; Surface de la Grille: 0 cm2; Volume de la Grille: 0 cm3
Baie 1905137 | Niveau 2 | 1905137 | 114 | 9006 | 1 | -746779066 | Description: _VTO_Baie; CTLG_EXTERNAL_LINK - 1, DocType: 9; 1, Tag: 211; 1, Crc: -732809594; IFC_Pset_Caractéristiques - ID: 1905137; Numérotation: 172; Numéro niveau: 05; Titre niveau: Niveau 2; IFC_Pset_Géométrie_Allège - Hauteur: 0 cm; Stratigraphie: ...; Épaisseur: 0 cm; IFC_Pset_Géométrie_Ébrasement - Présent: yes; Côté supérieur: no; Côté INFÉRIEUR: no; Épaisseur extérieure: 11 cm; Épaisseur latérale gauche: 3 cm; Épaisseur latérale droite: 3 cm; Épiasseur latérale supérieure: 3 cm; Épaisseur diagonale gauche: 0 cm; Épaisseur diagonale droite: 0 cm; Épaisseur diagonale inférieure: 0 cm; Épaisseur diagonale supérieure: 0 cm; Épaisseur intérieur: 0 cm; Données: [a : 110,00; b: 30,00; c: 0,00; d: 0,00] mm; IFC_Pset_Géométrie_Seuil - Type: Aucun; Épaisseur: 0 cm; Épaisseur interne: 0 cm; Décalage séparation: 0 cm; Appui extérieur: 0 cm; Appui intérieur: 0 cm; Côté latéral externe: 0 cm; Côté latéral interne: 0 cm; IFC_Pset_Géométrie_Chambranle - Position: Aucun; Épaisseur Chambranle intérieur: 0 cm; Longueur Chambranle intérieur: 0 cm; Superposition Chambranle intérieur: 0 cm; Épaisseur Intrados: 0 cm; Épaisseur Chambranle extérieur: 0 cm; Largeur Chambranle extérieur: 0 cm; Superposition Chambranle extérieur: 0 cm; Épaisseur Intrados extérieur: 0 cm; Décalage séparation intrados: 0 cm; IFC_Pset_Géométrie_CORNICHE depuis profil - Position: Aucune; sets with these values: 2; IFC_Pset_Géométrie_CORNICHE Extérieure à partir d'un profil - Décalage: 0; Angle: 0 deg; Symétrie: no; Fermer: no; sets with these values: 2; IFC_Pset_Géométrie_BASE Extérieure à partir d'un profil - Angle: 0 deg; Symétrie: no; Côté: 0 cm; sets with these values: 2; IFC_Pset_Géométrie - Côté extérieur: 1; Invertir (dte/gche): no; Invertir (intérieur/extérieur): yes; Forme: Rectangle; Largeur: 99.8095 cm; Hauteur: 136.089 cm; Hauteur 2: 0 cm; Rayon Arc: 0 cm; Rayon Cercle: 0 cm; Demi-axe horizontal: 0 cm; Demi-axe vertical: 0 cm; IFC_Pset_Géométrie_GRILLE - décalage: 0 cm; Offset latéral: 0 cm; Décalage supérieur: 0 cm; Décalage inférieur: 0 cm; Nombre accrochages latéraux: 0; Nombre d'accrochages supérieurs: 0; Nombre accrochages inférieurs: 0; IFC_Pset_Géométrie_Niche - Présent: no; Stratigraphie: Paroi en béton armé [120,00]; Épaisseur: 12 cm; Alignement: Intérieur; Décalage: 0 cm; IFC_Pset_Système de Référence Altimétrique_INFÉRIEUR - NIVEAU: Niveau 2 (Niveau 2 13545); delta: 91.6 cm; sous Niveau: <aucun>; IFC_Pset_Données Métré - Surface de l'Ouverture: 13600 cm2; Surface de l'Ébrasement: 4900 cm2; Surface du Seuil: 0 cm2; Surface du Seuil intérieur: 0 cm2; Volume du seuil: 0 cm3; Volume du seuil intérieur: 0 cm3; Surface de la Niche: 0 cm2; Surface de la Grille: 0 cm2; Volume de la Grille: 0 cm3
Baie 750235 | Niveau 2 | 750235 | 114 | 9006 | 1 | -746779066 | Description: _VTO_Baie; CTLG_EXTERNAL_LINK - 1, DocType: 9; 1, Tag: 211; 1, Crc: -732809594; IFC_Pset_Caractéristiques - ID: 750235; Numérotation: 152; Numéro niveau: 05; Titre niveau: Niveau 2; IFC_Pset_Géométrie_Allège - Hauteur: 0 cm; Stratigraphie: ...; Épaisseur: 0 cm; IFC_Pset_Géométrie_Ébrasement - Présent: yes; Côté supérieur: no; Côté INFÉRIEUR: no; Épaisseur extérieure: 11 cm; Épaisseur latérale gauche: 3 cm; Épaisseur latérale droite: 3 cm; Épiasseur latérale supérieure: 3 cm; Épaisseur diagonale gauche: 0 cm; Épaisseur diagonale droite: 0 cm; Épaisseur diagonale inférieure: 0 cm; Épaisseur diagonale supérieure: 0 cm; Épaisseur intérieur: 0 cm; Données: [a : 110,00; b: 30,00; c: 0,00; d: 0,00] mm; IFC_Pset_Géométrie_Seuil - Type: Aucun; Épaisseur: 0 cm; Épaisseur interne: 0 cm; Décalage séparation: 0 cm; Appui extérieur: 0 cm; Appui intérieur: 0 cm; Côté latéral externe: 0 cm; Côté latéral interne: 0 cm; IFC_Pset_Géométrie_Chambranle - Position: Aucun; Épaisseur Chambranle intérieur: 0 cm; Longueur Chambranle intérieur: 0 cm; Superposition Chambranle intérieur: 0 cm; Épaisseur Intrados: 0 cm; Épaisseur Chambranle extérieur: 0 cm; Largeur Chambranle extérieur: 0 cm; Superposition Chambranle extérieur: 0 cm; Épaisseur Intrados extérieur: 0 cm; Décalage séparation intrados: 0 cm; IFC_Pset_Géométrie_CORNICHE depuis profil - Position: Aucune; sets with these values: 2; IFC_Pset_Géométrie_CORNICHE Extérieure à partir d'un profil - Décalage: 0; Angle: 0 deg; Symétrie: no; Fermer: no; sets with these values: 2; IFC_Pset_Géométrie_BASE Extérieure à partir d'un profil - Angle: 0 deg; Symétrie: no; Côté: 0 cm; sets with these values: 2; IFC_Pset_Géométrie - Côté extérieur: 1; Invertir (dte/gche): no; Invertir (intérieur/extérieur): yes; Forme: Rectangle; Largeur: 44.3693 cm; Hauteur: 103.583 cm; Hauteur 2: 0 cm; Rayon Arc: 0 cm; Rayon Cercle: 0 cm; Demi-axe horizontal: 0 cm; Demi-axe vertical: 0 cm; IFC_Pset_Géométrie_GRILLE - décalage: 0 cm; Offset latéral: 0 cm; Décalage supérieur: 0 cm; Décalage inférieur: 0 cm; Nombre accrochages latéraux: 0; Nombre d'accrochages supérieurs: 0; Nombre accrochages inférieurs: 0; IFC_Pset_Géométrie_Niche - Présent: no; Stratigraphie: Paroi en béton armé [120,00]; Épaisseur: 12 cm; Alignement: Intérieur; Décalage: 0 cm; IFC_Pset_Système de Référence Altimétrique_INFÉRIEUR - NIVEAU: Niveau 2 (Niveau 2 13545); delta: 91.6084 cm; sous Niveau: <aucun>; IFC_Pset_Données Métré - Surface de l'Ouverture: 4600 cm2; Surface de l'Ébrasement: 3700 cm2; Surface du Seuil: 0 cm2; Surface du Seuil intérieur: 0 cm2; Volume du seuil: 0 cm3; Volume du seuil intérieur: 0 cm3; Surface de la Niche: 0 cm2; Surface de la Grille: 0 cm2; Volume de la Grille: 0 cm3
Baie 750239 | Niveau 2 | 750239 | 114 | 9006 | 1 | -746779066 | Description: _VTO_Baie; CTLG_EXTERNAL_LINK - 1, DocType: 9; 1, Tag: 211; 1, Crc: -732809594; IFC_Pset_Caractéristiques - ID: 750239; Numérotation: 154; Numéro niveau: 05; Titre niveau: Niveau 2; IFC_Pset_Géométrie_Allège - Hauteur: 0 cm; Stratigraphie: ...; Épaisseur: 0 cm; IFC_Pset_Géométrie_Ébrasement - Présent: yes; Côté supérieur: no; Côté INFÉRIEUR: no; Épaisseur extérieure: 11 cm; Épaisseur latérale gauche: 3 cm; Épaisseur latérale droite: 3 cm; Épiasseur latérale supérieure: 3 cm; Épaisseur diagonale gauche: 0 cm; Épaisseur diagonale droite: 0 cm; Épaisseur diagonale inférieure: 0 cm; Épaisseur diagonale supérieure: 0 cm; Épaisseur intérieur: 0 cm; Données: [a : 110,00; b: 30,00; c: 0,00; d: 0,00] mm; IFC_Pset_Géométrie_Seuil - Type: Aucun; Épaisseur: 0 cm; Épaisseur interne: 0 cm; Décalage séparation: 0 cm; Appui extérieur: 0 cm; Appui intérieur: 0 cm; Côté latéral externe: 0 cm; Côté latéral interne: 0 cm; IFC_Pset_Géométrie_Chambranle - Position: Aucun; Épaisseur Chambranle intérieur: 0 cm; Longueur Chambranle intérieur: 0 cm; Superposition Chambranle intérieur: 0 cm; Épaisseur Intrados: 0 cm; Épaisseur Chambranle extérieur: 0 cm; Largeur Chambranle extérieur: 0 cm; Superposition Chambranle extérieur: 0 cm; Épaisseur Intrados extérieur: 0 cm; Décalage séparation intrados: 0 cm; IFC_Pset_Géométrie_CORNICHE depuis profil - Position: Aucune; sets with these values: 2; IFC_Pset_Géométrie_CORNICHE Extérieure à partir d'un profil - Décalage: 0; Angle: 0 deg; Symétrie: no; Fermer: no; sets with these values: 2; IFC_Pset_Géométrie_BASE Extérieure à partir d'un profil - Angle: 0 deg; Symétrie: no; Côté: 0 cm; sets with these values: 2; IFC_Pset_Géométrie - Côté extérieur: 1; Invertir (dte/gche): no; Invertir (intérieur/extérieur): yes; Forme: Rectangle; Largeur: 39.5994 cm; Hauteur: 100 cm; Hauteur 2: 0 cm; Rayon Arc: 0 cm; Rayon Cercle: 0 cm; Demi-axe horizontal: 0 cm; Demi-axe vertical: 0 cm; IFC_Pset_Géométrie_GRILLE - décalage: 0 cm; Offset latéral: 0 cm; Décalage supérieur: 0 cm; Décalage inférieur: 0 cm; Nombre accrochages latéraux: 0; Nombre d'accrochages supérieurs: 0; Nombre accrochages inférieurs: 0; IFC_Pset_Géométrie_Niche - Présent: no; Stratigraphie: Paroi en béton armé [120,00]; Épaisseur: 12 cm; Alignement: Intérieur; Décalage: 0 cm; IFC_Pset_Système de Référence Altimétrique_INFÉRIEUR - NIVEAU: Niveau 2 (Niveau 2 13545); delta: 91.6 cm; sous Niveau: <aucun>; IFC_Pset_Données Métré - Surface de l'Ouverture: 4000 cm2; Surface de l'Ébrasement: 3600 cm2; Surface du Seuil: 0 cm2; Surface du Seuil intérieur: 0 cm2; Volume du seuil: 0 cm3; Volume du seuil intérieur: 0 cm3; Surface de la Niche: 0 cm2; Surface de la Grille: 0 cm2; Volume de la Grille: 0 cm3
Baie 750240 | Niveau 2 | 750240 | 114 | 9006 | 1 | -746779066 | Description: _VTO_Baie; CTLG_EXTERNAL_LINK - 1, DocType: 9; 1, Tag: 211; 1, Crc: -732809594; IFC_Pset_Caractéristiques - ID: 750240; Numérotation: 155; Numéro niveau: 05; Titre niveau: Niveau 2; IFC_Pset_Géométrie_Allège - Hauteur: 0 cm; Stratigraphie: ...; Épaisseur: 0 cm; IFC_Pset_Géométrie_Ébrasement - Présent: yes; Côté supérieur: no; Côté INFÉRIEUR: no; Épaisseur extérieure: 11 cm; Épaisseur latérale gauche: 3 cm; Épaisseur latérale droite: 3 cm; Épiasseur latérale supérieure: 3 cm; Épaisseur diagonale gauche: 0 cm; Épaisseur diagonale droite: 0 cm; Épaisseur diagonale inférieure: 0 cm; Épaisseur diagonale supérieure: 0 cm; Épaisseur intérieur: 0 cm; Données: [a : 110,00; b: 30,00; c: 0,00; d: 0,00] mm; IFC_Pset_Géométrie_Seuil - Type: Aucun; Épaisseur: 0 cm; Épaisseur interne: 0 cm; Décalage séparation: 0 cm; Appui extérieur: 0 cm; Appui intérieur: 0 cm; Côté latéral externe: 0 cm; Côté latéral interne: 0 cm; IFC_Pset_Géométrie_Chambranle - Position: Aucun; Épaisseur Chambranle intérieur: 0 cm; Longueur Chambranle intérieur: 0 cm; Superposition Chambranle intérieur: 0 cm; Épaisseur Intrados: 0 cm; Épaisseur Chambranle extérieur: 0 cm; Largeur Chambranle extérieur: 0 cm; Superposition Chambranle extérieur: 0 cm; Épaisseur Intrados extérieur: 0 cm; Décalage séparation intrados: 0 cm; IFC_Pset_Géométrie_CORNICHE depuis profil - Position: Aucune; sets with these values: 2; IFC_Pset_Géométrie_CORNICHE Extérieure à partir d'un profil - Décalage: 0; Angle: 0 deg; Symétrie: no; Fermer: no; sets with these values: 2; IFC_Pset_Géométrie_BASE Extérieure à partir d'un profil - Angle: 0 deg; Symétrie: no; Côté: 0 cm; sets with these values: 2; IFC_Pset_Géométrie - Côté extérieur: 1; Invertir (dte/gche): no; Invertir (intérieur/extérieur): yes; Forme: Rectangle; Largeur: 40.2645 cm; Hauteur: 100 cm; Hauteur 2: 0 cm; Rayon Arc: 0 cm; Rayon Cercle: 0 cm; Demi-axe horizontal: 0 cm; Demi-axe vertical: 0 cm; IFC_Pset_Géométrie_GRILLE - décalage: 0 cm; Offset latéral: 0 cm; Décalage supérieur: 0 cm; Décalage inférieur: 0 cm; Nombre accrochages latéraux: 0; Nombre d'accrochages supérieurs: 0; Nombre accrochages inférieurs: 0; IFC_Pset_Géométrie_Niche - Présent: no; Stratigraphie: Paroi en béton armé [120,00]; Épaisseur: 12 cm; Alignement: Intérieur; Décalage: 0 cm; IFC_Pset_Système de Référence Altimétrique_INFÉRIEUR - NIVEAU: Niveau 2 (Niveau 2 13545); delta: 91.6 cm; sous Niveau: <aucun>; IFC_Pset_Données Métré - Surface de l'Ouverture: 4000 cm2; Surface de l'Ébrasement: 3600 cm2; Surface du Seuil: 0 cm2; Surface du Seuil intérieur: 0 cm2; Volume du seuil: 0 cm3; Volume du seuil intérieur: 0 cm3; Surface de la Niche: 0 cm2; Surface de la Grille: 0 cm2; Volume de la Grille: 0 cm3
Baie 736907 | Niveau 2 | 736907 | 114 | 9006 | 1 | -746779066 | Description: _VTO_Baie; CTLG_EXTERNAL_LINK - 1, DocType: 9; 1, Tag: 211; 1, Crc: -732809594; IFC_Pset_Caractéristiques - ID: 736907; Numérotation: 138; Numéro niveau: 05; Titre niveau: Niveau 2; IFC_Pset_Géométrie_Allège - Hauteur: 0 cm; Stratigraphie: ...; Épaisseur: 0 cm; IFC_Pset_Géométrie_Ébrasement - Présent: yes; Côté supérieur: no; Côté INFÉRIEUR: no; Épaisseur extérieure: 8 cm; Épaisseur latérale gauche: 3 cm; Épaisseur latérale droite: 3 cm; Épiasseur latérale supérieure: 3 cm; Épaisseur diagonale gauche: 0 cm; Épaisseur diagonale droite: 0 cm; Épaisseur diagonale inférieure: 0 cm; Épaisseur diagonale supérieure: 0 cm; Épaisseur intérieur: 0 cm; Données: [a : 80,00; b: 30,00; c: 0,00; d: 0,00] mm; IFC_Pset_Géométrie_Seuil - Type: Aucun; Épaisseur: 0 cm; Épaisseur interne: 0 cm; Décalage séparation: 0 cm; Appui extérieur: 0 cm; Appui intérieur: 0 cm; Côté latéral externe: 0 cm; Côté latéral interne: 0 cm; IFC_Pset_Géométrie_Chambranle - Position: Aucun; Épaisseur Chambranle intérieur: 0 cm; Longueur Chambranle intérieur: 0 cm; Superposition Chambranle intérieur: 0 cm; Épaisseur Intrados: 0 cm; Épaisseur Chambranle extérieur: 0 cm; Largeur Chambranle extérieur: 0 cm; Superposition Chambranle extérieur: 0 cm; Épaisseur Intrados extérieur: 0 cm; Décalage séparation intrados: 0 cm; IFC_Pset_Géométrie_CORNICHE depuis profil - Position: Aucune; sets with these values: 2; IFC_Pset_Géométrie_CORNICHE Extérieure à partir d'un profil - Décalage: 0; Angle: 0 deg; Symétrie: no; Fermer: no; sets with these values: 2; IFC_Pset_Géométrie_BASE Extérieure à partir d'un profil - Angle: 0 deg; Symétrie: no; Côté: 0 cm; sets with these values: 2; IFC_Pset_Géométrie - Côté extérieur: 0; Invertir (dte/gche): no; Invertir (intérieur/extérieur): no; Forme: Rectangle; Largeur: 99.5479 cm; Hauteur: 184.527 cm; Hauteur 2: 0 cm; Rayon Arc: 0 cm; Rayon Cercle: 0 cm; Demi-axe horizontal: 0 cm; Demi-axe vertical: 0 cm; IFC_Pset_Géométrie_GRILLE - décalage: 0 cm; Offset latéral: 0 cm; Décalage supérieur: 0 cm; Décalage inférieur: 0 cm; Nombre accrochages latéraux: 0; Nombre d'accrochages supérieurs: 0; Nombre accrochages inférieurs: 0; IFC_Pset_Géométrie_Niche - Présent: no; Stratigraphie: Paroi en béton armé [120,00]; Épaisseur: 12 cm; Alignement: Intérieur; Décalage: 0 cm; IFC_Pset_Système de Référence Altimétrique_INFÉRIEUR - NIVEAU: Niveau 2 (Niveau 2 13545); delta: 49.8342 cm; sous Niveau: <aucun>; IFC_Pset_Données Métré - Surface de l'Ouverture: 18400 cm2; Surface de l'Ébrasement: 5500 cm2; Surface du Seuil: 0 cm2; Surface du Seuil intérieur: 0 cm2; Volume du seuil: 0 cm3; Volume du seuil intérieur: 0 cm3; Surface de la Niche: 0 cm2; Surface de la Grille: 0 cm2; Volume de la Grille: 0 cm3
Baie 736908 | Niveau 2 | 736908 | 114 | 9006 | 1 | -746779066 | Description: _VTO_Baie; CTLG_EXTERNAL_LINK - 1, DocType: 9; 1, Tag: 211; 1, Crc: -732809594; IFC_Pset_Caractéristiques - ID: 736908; Numérotation: 139; Numéro niveau: 05; Titre niveau: Niveau 2; IFC_Pset_Géométrie_Allège - Hauteur: 0 cm; Stratigraphie: ...; Épaisseur: 0 cm; IFC_Pset_Géométrie_Ébrasement - Présent: yes; Côté supérieur: no; Côté INFÉRIEUR: no; Épaisseur extérieure: 8 cm; Épaisseur latérale gauche: 3 cm; Épaisseur latérale droite: 3 cm; Épiasseur latérale supérieure: 3 cm; Épaisseur diagonale gauche: 0 cm; Épaisseur diagonale droite: 0 cm; Épaisseur diagonale inférieure: 0 cm; Épaisseur diagonale supérieure: 0 cm; Épaisseur intérieur: 0 cm; Données: [a : 80,00; b: 30,00; c: 0,00; d: 0,00] mm; IFC_Pset_Géométrie_Seuil - Type: Aucun; Épaisseur: 0 cm; Épaisseur interne: 0 cm; Décalage séparation: 0 cm; Appui extérieur: 0 cm; Appui intérieur: 0 cm; Côté latéral externe: 0 cm; Côté latéral interne: 0 cm; IFC_Pset_Géométrie_Chambranle - Position: Aucun; Épaisseur Chambranle intérieur: 0 cm; Longueur Chambranle intérieur: 0 cm; Superposition Chambranle intérieur: 0 cm; Épaisseur Intrados: 0 cm; Épaisseur Chambranle extérieur: 0 cm; Largeur Chambranle extérieur: 0 cm; Superposition Chambranle extérieur: 0 cm; Épaisseur Intrados extérieur: 0 cm; Décalage séparation intrados: 0 cm; IFC_Pset_Géométrie_CORNICHE depuis profil - Position: Aucune; sets with these values: 2; IFC_Pset_Géométrie_CORNICHE Extérieure à partir d'un profil - Décalage: 0; Angle: 0 deg; Symétrie: no; Fermer: no; sets with these values: 2; IFC_Pset_Géométrie_BASE Extérieure à partir d'un profil - Angle: 0 deg; Symétrie: no; Côté: 0 cm; sets with these values: 2; IFC_Pset_Géométrie - Côté extérieur: 0; Invertir (dte/gche): no; Invertir (intérieur/extérieur): no; Forme: Rectangle; Largeur: 98.877 cm; Hauteur: 180 cm; Hauteur 2: 0 cm; Rayon Arc: 0 cm; Rayon Cercle: 0 cm; Demi-axe horizontal: 0 cm; Demi-axe vertical: 0 cm; IFC_Pset_Géométrie_GRILLE - décalage: 0 cm; Offset latéral: 0 cm; Décalage supérieur: 0 cm; Décalage inférieur: 0 cm; Nombre accrochages latéraux: 0; Nombre d'accrochages supérieurs: 0; Nombre accrochages inférieurs: 0; IFC_Pset_Géométrie_Niche - Présent: no; Stratigraphie: Paroi en béton armé [120,00]; Épaisseur: 12 cm; Alignement: Intérieur; Décalage: 0 cm; IFC_Pset_Système de Référence Altimétrique_INFÉRIEUR - NIVEAU: Niveau 2 (Niveau 2 13545); delta: 55 cm; sous Niveau: <aucun>; IFC_Pset_Données Métré - Surface de l'Ouverture: 17800 cm2; Surface de l'Ébrasement: 5400 cm2; Surface du Seuil: 0 cm2; Surface du Seuil intérieur: 0 cm2; Volume du seuil: 0 cm3; Volume du seuil intérieur: 0 cm3; Surface de la Niche: 0 cm2; Surface de la Grille: 0 cm2; Volume de la Grille: 0 cm3
Baie 738682 | Niveau 2 | 738682 | 114 | 9006 | 1 | -746779066 | Description: _VTO_Baie; CTLG_EXTERNAL_LINK - 1, DocType: 9; 1, Tag: 211; 1, Crc: -732809594; IFC_Pset_Caractéristiques - ID: 738682; Numérotation: 140; Numéro niveau: 05; Titre niveau: Niveau 2; IFC_Pset_Géométrie_Allège - Hauteur: 0 cm; Stratigraphie: ...; Épaisseur: 0 cm; IFC_Pset_Géométrie_Ébrasement - Présent: yes; Côté supérieur: no; Côté INFÉRIEUR: no; Épaisseur extérieure: 6 cm; Épaisseur latérale gauche: 3 cm; Épaisseur latérale droite: 3 cm; Épiasseur latérale supérieure: 3 cm; Épaisseur diagonale gauche: 0 cm; Épaisseur diagonale droite: 0 cm; Épaisseur diagonale inférieure: 0 cm; Épaisseur diagonale supérieure: 0 cm; Épaisseur intérieur: 0 cm; Données: [a : 60,00; b: 30,00; c: 0,00; d: 0,00] mm; IFC_Pset_Géométrie_Seuil - Type: Aucun; Épaisseur: 0 cm; Épaisseur interne: 0 cm; Décalage séparation: 0 cm; Appui extérieur: 0 cm; Appui intérieur: 0 cm; Côté latéral externe: 0 cm; Côté latéral interne: 0 cm; IFC_Pset_Géométrie_Chambranle - Position: Aucun; Épaisseur Chambranle intérieur: 0 cm; Longueur Chambranle intérieur: 0 cm; Superposition Chambranle intérieur: 0 cm; Épaisseur Intrados: 0 cm; Épaisseur Chambranle extérieur: 0 cm; Largeur Chambranle extérieur: 0 cm; Superposition Chambranle extérieur: 0 cm; Épaisseur Intrados extérieur: 0 cm; Décalage séparation intrados: 0 cm; IFC_Pset_Géométrie_CORNICHE depuis profil - Position: Aucune; sets with these values: 2; IFC_Pset_Géométrie_CORNICHE Extérieure à partir d'un profil - Décalage: 0; Angle: 0 deg; Symétrie: no; Fermer: no; sets with these values: 2; IFC_Pset_Géométrie_BASE Extérieure à partir d'un profil - Angle: 0 deg; Symétrie: no; Côté: 0 cm; sets with these values: 2; IFC_Pset_Géométrie - Côté extérieur: 0; Invertir (dte/gche): no; Invertir (intérieur/extérieur): no; Forme: Rectangle; Largeur: 39.5994 cm; Hauteur: 120.208 cm; Hauteur 2: 0 cm; Rayon Arc: 0 cm; Rayon Cercle: 0 cm; Demi-axe horizontal: 0 cm; Demi-axe vertical: 0 cm; IFC_Pset_Géométrie_GRILLE - décalage: 0 cm; Offset latéral: 0 cm; Décalage supérieur: 0 cm; Décalage inférieur: 0 cm; Nombre accrochages latéraux: 0; Nombre d'accrochages supérieurs: 0; Nombre accrochages inférieurs: 0; IFC_Pset_Géométrie_Niche - Présent: no; Stratigraphie: Paroi en béton armé [120,00]; Épaisseur: 12 cm; Alignement: Intérieur; Décalage: 0 cm; IFC_Pset_Système de Référence Altimétrique_INFÉRIEUR - NIVEAU: Niveau 2 (Niveau 2 13545); delta: 51.6522 cm; sous Niveau: <aucun>; IFC_Pset_Données Métré - Surface de l'Ouverture: 4800 cm2; Surface de l'Ébrasement: 3100 cm2; Surface du Seuil: 0 cm2; Surface du Seuil intérieur: 0 cm2; Volume du seuil: 0 cm3; Volume du seuil intérieur: 0 cm3; Surface de la Niche: 0 cm2; Surface de la Grille: 0 cm2; Volume de la Grille: 0 cm3
Baie 738683 | Niveau 2 | 738683 | 114 | 9006 | 1 | -746779066 | Description: _VTO_Baie; CTLG_EXTERNAL_LINK - 1, DocType: 9; 1, Tag: 211; 1, Crc: -732809594; IFC_Pset_Caractéristiques - ID: 738683; Numérotation: 141; Numéro niveau: 05; Titre niveau: Niveau 2; IFC_Pset_Géométrie_Allège - Hauteur: 0 cm; Stratigraphie: ...; Épaisseur: 0 cm; IFC_Pset_Géométrie_Ébrasement - Présent: yes; Côté supérieur: no; Côté INFÉRIEUR: no; Épaisseur extérieure: 6 cm; Épaisseur latérale gauche: 3 cm; Épaisseur latérale droite: 3 cm; Épiasseur latérale supérieure: 3 cm; Épaisseur diagonale gauche: 0 cm; Épaisseur diagonale droite: 0 cm; Épaisseur diagonale inférieure: 0 cm; Épaisseur diagonale supérieure: 0 cm; Épaisseur intérieur: 0 cm; Données: [a : 60,00; b: 30,00; c: 0,00; d: 0,00] mm; IFC_Pset_Géométrie_Seuil - Type: Aucun; Épaisseur: 0 cm; Épaisseur interne: 0 cm; Décalage séparation: 0 cm; Appui extérieur: 0 cm; Appui intérieur: 0 cm; Côté latéral externe: 0 cm; Côté latéral interne: 0 cm; IFC_Pset_Géométrie_Chambranle - Position: Aucun; Épaisseur Chambranle intérieur: 0 cm; Longueur Chambranle intérieur: 0 cm; Superposition Chambranle intérieur: 0 cm; Épaisseur Intrados: 0 cm; Épaisseur Chambranle extérieur: 0 cm; Largeur Chambranle extérieur: 0 cm; Superposition Chambranle extérieur: 0 cm; Épaisseur Intrados extérieur: 0 cm; Décalage séparation intrados: 0 cm; IFC_Pset_Géométrie_CORNICHE depuis profil - Position: Aucune; sets with these values: 2; IFC_Pset_Géométrie_CORNICHE Extérieure à partir d'un profil - Décalage: 0; Angle: 0 deg; Symétrie: no; Fermer: no; sets with these values: 2; IFC_Pset_Géométrie_BASE Extérieure à partir d'un profil - Angle: 0 deg; Symétrie: no; Côté: 0 cm; sets with these values: 2; IFC_Pset_Géométrie - Côté extérieur: 0; Invertir (dte/gche): no; Invertir (intérieur/extérieur): no; Forme: Rectangle; Largeur: 39.5994 cm; Hauteur: 120.208 cm; Hauteur 2: 0 cm; Rayon Arc: 0 cm; Rayon Cercle: 0 cm; Demi-axe horizontal: 0 cm; Demi-axe vertical: 0 cm; IFC_Pset_Géométrie_GRILLE - décalage: 0 cm; Offset latéral: 0 cm; Décalage supérieur: 0 cm; Décalage inférieur: 0 cm; Nombre accrochages latéraux: 0; Nombre d'accrochages supérieurs: 0; Nombre accrochages inférieurs: 0; IFC_Pset_Géométrie_Niche - Présent: no; Stratigraphie: Paroi en béton armé [120,00]; Épaisseur: 12 cm; Alignement: Intérieur; Décalage: 0 cm; IFC_Pset_Système de Référence Altimétrique_INFÉRIEUR - NIVEAU: Niveau 2 (Niveau 2 13545); delta: 52 cm; sous Niveau: <aucun>; IFC_Pset_Données Métré - Surface de l'Ouverture: 4800 cm2; Surface de l'Ébrasement: 3100 cm2; Surface du Seuil: 0 cm2; Surface du Seuil intérieur: 0 cm2; Volume du seuil: 0 cm3; Volume du seuil intérieur: 0 cm3; Surface de la Niche: 0 cm2; Surface de la Grille: 0 cm2; Volume de la Grille: 0 cm3
4294966484_11 | Niveau 2 | -812 | 2002 | 2002 | 0 | -1292786862
4294966485_11 | Niveau 2 | -811 | 2002 | 2002 | 0 | -1292786862
4294966381_11 | Niveau 2 | -915 | 2002 | 2002 | 0 | -1292786862
Baie 1533937 | Niveau 2 | 1533937 | 114 | 9006 | 1 | -746779066 | Description: _VTO_Baie; CTLG_EXTERNAL_LINK - 1, DocType: 9; 1, Tag: 211; 1, Crc: -1554559915; IFC_Pset_Caractéristiques - ID: 1533937; Numérotation: 170; Numéro niveau: 05; Titre niveau: Niveau 2; IFC_Pset_Géométrie_Allège - Hauteur: 0 cm; Stratigraphie: ...; Épaisseur: 0 cm; IFC_Pset_Géométrie_Ébrasement - Présent: no; Côté supérieur: no; Côté INFÉRIEUR: no; Épaisseur extérieure: 0 cm; Épaisseur latérale gauche: 0 cm; Épaisseur latérale droite: 0 cm; Épiasseur latérale supérieure: 0 cm; Épaisseur diagonale gauche: 0 cm; Épaisseur diagonale droite: 0 cm; Épaisseur diagonale inférieure: 0 cm; Épaisseur diagonale supérieure: 0 cm; Épaisseur intérieur: 0 cm; IFC_Pset_Géométrie_Seuil - Type: Aucun; Épaisseur: 0 cm; Épaisseur interne: 0 cm; Décalage séparation: 0 cm; Appui extérieur: 0 cm; Appui intérieur: 0 cm; Côté latéral externe: 0 cm; Côté latéral interne: 0 cm; IFC_Pset_Géométrie_Chambranle - Position: Aucun; Épaisseur Chambranle intérieur: 0 cm; Longueur Chambranle intérieur: 0 cm; Superposition Chambranle intérieur: 0 cm; Épaisseur Intrados: 0 cm; Épaisseur Chambranle extérieur: 0 cm; Largeur Chambranle extérieur: 0 cm; Superposition Chambranle extérieur: 0 cm; Épaisseur Intrados extérieur: 0 cm; Décalage séparation intrados: 0 cm; IFC_Pset_Géométrie_CORNICHE depuis profil - Position: Aucune; sets with these values: 2; IFC_Pset_Géométrie_CORNICHE Extérieure à partir d'un profil - Décalage: 0; Angle: 0 deg; Symétrie: no; Fermer: no; sets with these values: 2; IFC_Pset_Géométrie_BASE Extérieure à partir d'un profil - Angle: 0 deg; Symétrie: no; Côté: 0 cm; sets with these values: 2; IFC_Pset_Géométrie - Côté extérieur: 0; Invertir (dte/gche): no; Invertir (intérieur/extérieur): no; Forme: Rectangle; Largeur: 166.963 cm; Hauteur: 221.6 cm; Hauteur 2: 0 cm; Rayon Arc: 0 cm; Rayon Cercle: 0 cm; Demi-axe horizontal: 0 cm; Demi-axe vertical: 0 cm; IFC_Pset_Géométrie_GRILLE - décalage: 0 cm; Offset latéral: 0 cm; Décalage supérieur: 0 cm; Décalage inférieur: 0 cm; Nombre accrochages latéraux: 0; Nombre d'accrochages supérieurs: 0; Nombre accrochages inférieurs: 0; IFC_Pset_Géométrie_Niche - Présent: no; Stratigraphie: default [80,00]; Épaisseur: 8 cm; Alignement: Intérieur; Décalage: 0 cm; IFC_Pset_Système de Référence Altimétrique_INFÉRIEUR - NIVEAU: Niveau 2 (Niveau 2 13545); delta: 2 cm; sous Niveau: <aucun>; IFC_Pset_Données Métré - Surface de l'Ouverture: 37000 cm2; Surface de l'Ébrasement: 0 cm2; Surface du Seuil: 0 cm2; Surface du Seuil intérieur: 0 cm2; Volume du seuil: 0 cm3; Volume du seuil intérieur: 0 cm3; Surface de la Niche: 0 cm2; Surface de la Grille: 0 cm2; Volume de la Grille: 0 cm3
4294966386_11 | Niveau 2 | -910 | 2002 | 2002 | 0 | -1292786862
4294966376_11 | Niveau 2 | -920 | 2002 | 2002 | 0 | -1292786862
4294966527_11 | Niveau 2 | -769 | 2002 | 2002 | 0 | -1292786862
4294966501_11 | Niveau 2 | -795 | 2002 | 2002 | 0 | -1292786862
4294966504_11 | Niveau 2 | -792 | 2002 | 2002 | 0 | -1292786862
4294966528_11 | Niveau 2 | -768 | 2002 | 2002 | 0 | -1292786862
4294966525_11 | Niveau 2 | -771 | 2002 | 2002 | 0 | -1292786862
4294966405_11 | Niveau 2 | -891 | 2002 | 2002 | 0 | -1292786862
4294966439_11 | Niveau 2 | -857 | 2002 | 2002 | 0 | -1292786862
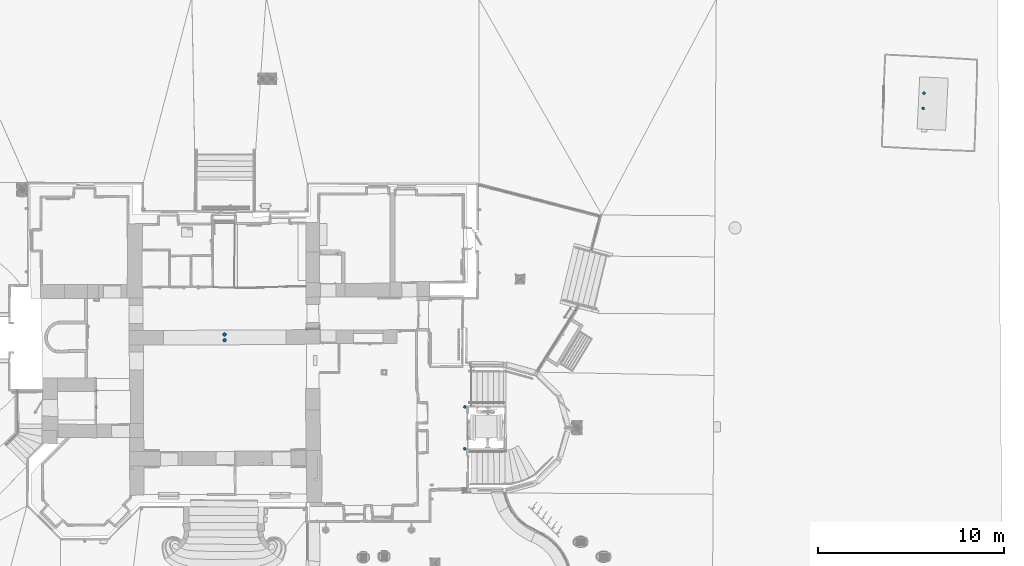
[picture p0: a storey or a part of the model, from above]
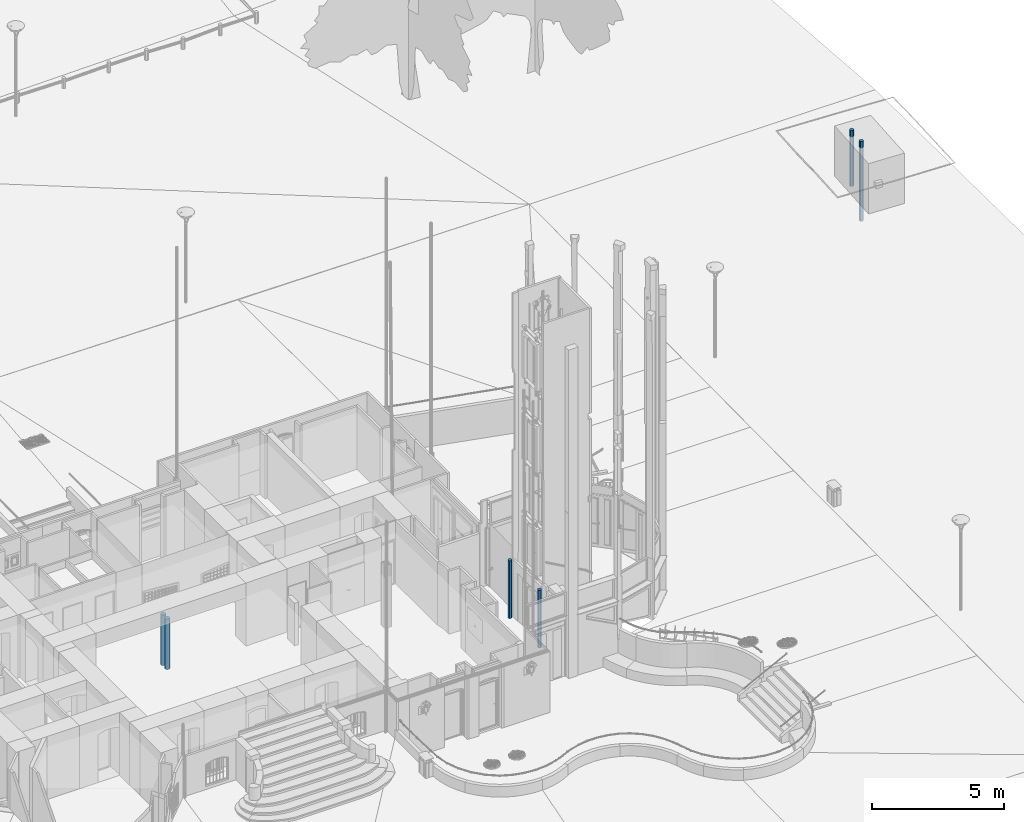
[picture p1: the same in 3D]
Properties of the parts of a building model (IFC2X3), part 16 of 37

# IfcOpeningElement: Opening (367)
Name | In | __RECOGNIZE__, ID | TPLG | TPLG_OD | GENERATE | 0, Crc
4294966403_11 | Niveau 2 | -893 | 2002 | 2002 | 0 | -1292786862
4294966406_11 | Niveau 2 | -890 | 2002 | 2002 | 0 | -1292786862
4294966444_11 | Niveau 2 | -852 | 2002 | 2002 | 0 | -1292786862
4294966443_11 | Niveau 2 | -853 | 2002 | 2002 | 0 | -1292786862
4294966374_11 | Niveau 2 | -922 | 2002 | 2002 | 0 | -1292786862
4294966407_11 | Niveau 2 | -889 | 2002 | 2002 | 0 | -1292786862
4294966390_11 | Niveau 2 | -906 | 2002 | 2002 | 0 | -1292786862
4294966522_11 | Niveau 2 | -774 | 2002 | 2002 | 0 | -1292786862
4294966521_11 | Niveau 2 | -775 | 2002 | 2002 | 0 | -1292786862
4294966377_11 | Niveau 2 | -919 | 2002 | 2002 | 0 | -1292786862
4294966373_11 | Niveau 2 | -923 | 2002 | 2002 | 0 | -1292786862
Baie 171995 | Niveau 2 | 171995 | 114 | 9006 | 1 | -746779066 | Description: _VTO_Baie; CTLG_EXTERNAL_LINK - 1, DocType: 9; 1, Tag: 211; 1, Crc: 1656458995; IFC_Pset_Caractéristiques - ID: 171995; Numérotation: 044; Numéro niveau: 05; Titre niveau: Niveau 2; IFC_Pset_Géométrie_Allège - Hauteur: 0 cm; Stratigraphie: ...; Épaisseur: 0 cm; IFC_Pset_Géométrie_Ébrasement - Présent: no; Côté supérieur: no; Côté INFÉRIEUR: no; Épaisseur extérieure: 0 cm; Épaisseur latérale gauche: 0 cm; Épaisseur latérale droite: 0 cm; Épiasseur latérale supérieure: 0 cm; Épaisseur diagonale gauche: 0 cm; Épaisseur diagonale droite: 0 cm; Épaisseur diagonale inférieure: 0 cm; Épaisseur diagonale supérieure: 0 cm; Épaisseur intérieur: 0 cm; IFC_Pset_Géométrie_Seuil - Type: Aucun; Épaisseur: 0 cm; Épaisseur interne: 0 cm; Décalage séparation: 0 cm; Appui extérieur: 0 cm; Appui intérieur: 0 cm; Côté latéral externe: 0 cm; Côté latéral interne: 0 cm; IFC_Pset_Géométrie_Chambranle - Position: Aucun; Épaisseur Chambranle intérieur: 0 cm; Longueur Chambranle intérieur: 0 cm; Superposition Chambranle intérieur: 0 cm; Épaisseur Intrados: 0 cm; Épaisseur Chambranle extérieur: 0 cm; Largeur Chambranle extérieur: 0 cm; Superposition Chambranle extérieur: 0 cm; Épaisseur Intrados extérieur: 0 cm; Décalage séparation intrados: 0 cm; IFC_Pset_Géométrie_CORNICHE depuis profil - Position: Aucune; sets with these values: 2; IFC_Pset_Géométrie_CORNICHE Extérieure à partir d'un profil - Décalage: 0; Angle: 0 deg; Symétrie: no; Fermer: no; sets with these values: 2; IFC_Pset_Géométrie_BASE Extérieure à partir d'un profil - Angle: 0 deg; Symétrie: no; Côté: 0 cm; sets with these values: 2; IFC_Pset_Géométrie - Côté extérieur: 0; Invertir (dte/gche): no; Invertir (intérieur/extérieur): no; Forme: Rectangle; Largeur: 76.0641 cm; Hauteur: 202 cm; Hauteur 2: 0 cm; Rayon Arc: 0 cm; Rayon Cercle: 0 cm; Demi-axe horizontal: 0 cm; Demi-axe vertical: 0 cm; IFC_Pset_Géométrie_GRILLE - décalage: 0 cm; Offset latéral: 0 cm; Décalage supérieur: 0 cm; Décalage inférieur: 0 cm; Nombre accrochages latéraux: 0; Nombre d'accrochages supérieurs: 0; Nombre accrochages inférieurs: 0; IFC_Pset_Géométrie_Niche - Présent: no; Stratigraphie: default [150,00]; Épaisseur: 15 cm; Alignement: Intérieur; Décalage: 0 cm; IFC_Pset_Système de Référence Altimétrique_INFÉRIEUR - NIVEAU: Niveau 2 (Niveau 2 13545); delta: 1.42109e-12 cm; sous Niveau: <aucun>; IFC_Pset_Données Métré - Surface de l'Ouverture: 15400 cm2; Surface de l'Ébrasement: 0 cm2; Surface du Seuil: 0 cm2; Surface du Seuil intérieur: 0 cm2; Volume du seuil: 0 cm3; Volume du seuil intérieur: 0 cm3; Surface de la Niche: 0 cm2; Surface de la Grille: 0 cm2; Volume de la Grille: 0 cm3
4294966524_11 | Niveau 2 | -772 | 2002 | 2002 | 0 | -1292786862
4294966523_11 | Niveau 2 | -773 | 2002 | 2002 | 0 | -1292786862
4294966431_11 | Niveau 2 | -865 | 2002 | 2002 | 0 | -1292786862
4294966379_11 | Niveau 2 | -917 | 2002 | 2002 | 0 | -1292786862
4294966434_11 | Niveau 2 | -862 | 2002 | 2002 | 0 | -1292786862
4294966438_11 | Niveau 2 | -858 | 2002 | 2002 | 0 | -1292786862
4294966436_11 | Niveau 2 | -860 | 2002 | 2002 | 0 | -1292786862
4294966435_11 | Niveau 2 | -861 | 2002 | 2002 | 0 | -1292786862
4294966437_11 | Niveau 2 | -859 | 2002 | 2002 | 0 | -1292786862
4294966432_11 | Niveau 2 | -864 | 2002 | 2002 | 0 | -1292786862
4294966408_11 | Niveau 2 | -888 | 2002 | 2002 | 0 | -1292786862
4294966404_11 | Niveau 2 | -892 | 2002 | 2002 | 0 | -1292786862
4294966375_11 | Niveau 2 | -921 | 2002 | 2002 | 0 | -1292786862
4294966500_11 | Mezzanine | -796 | 2002 | 2002 | 0 | -1292786862
Baie 973536 | Mezzanine | 973536 | 114 | 9006 | 1 | -746779066 | Description: _VTO_Baie; CTLG_EXTERNAL_LINK - 1, DocType: 9; 1, Tag: 211; 1, Crc: -732809594; IFC_Pset_Caractéristiques - ID: 973536; Numérotation: 159; Numéro niveau: 06; Titre niveau: Mezzanine; IFC_Pset_Géométrie_Allège - Hauteur: 0 cm; Stratigraphie: ...; Épaisseur: 0 cm; IFC_Pset_Géométrie_Ébrasement - Présent: no; Côté supérieur: no; Côté INFÉRIEUR: no; Épaisseur extérieure: 0 cm; Épaisseur latérale gauche: 0 cm; Épaisseur latérale droite: 0 cm; Épiasseur latérale supérieure: 0 cm; Épaisseur diagonale gauche: 0 cm; Épaisseur diagonale droite: 0 cm; Épaisseur diagonale inférieure: 0 cm; Épaisseur diagonale supérieure: 0 cm; Épaisseur intérieur: 0 cm; IFC_Pset_Géométrie_Seuil - Type: Aucun; Épaisseur: 0 cm; Épaisseur interne: 0 cm; Décalage séparation: 0 cm; Appui extérieur: 0 cm; Appui intérieur: 0 cm; Côté latéral externe: 0 cm; Côté latéral interne: 0 cm; IFC_Pset_Géométrie_Chambranle - Position: Aucun; Épaisseur Chambranle intérieur: 0 cm; Longueur Chambranle intérieur: 0 cm; Superposition Chambranle intérieur: 0 cm; Épaisseur Intrados: 0 cm; Épaisseur Chambranle extérieur: 0 cm; Largeur Chambranle extérieur: 0 cm; Superposition Chambranle extérieur: 0 cm; Épaisseur Intrados extérieur: 0 cm; Décalage séparation intrados: 0 cm; IFC_Pset_Géométrie_CORNICHE depuis profil - Position: Aucune; sets with these values: 2; IFC_Pset_Géométrie_CORNICHE Extérieure à partir d'un profil - Décalage: 0; Angle: 0 deg; Symétrie: no; Fermer: no; sets with these values: 2; IFC_Pset_Géométrie_BASE Extérieure à partir d'un profil - Angle: 0 deg; Symétrie: no; Côté: 0 cm; sets with these values: 2; IFC_Pset_Géométrie - Côté extérieur: 0; Invertir (dte/gche): no; Invertir (intérieur/extérieur): no; Forme: Cercle; Largeur: 0 cm; Hauteur: 0 cm; Hauteur 2: 0 cm; Rayon Arc: 0 cm; Rayon Cercle: 31.5 cm; Demi-axe horizontal: 0 cm; Demi-axe vertical: 0 cm; IFC_Pset_Géométrie_GRILLE - décalage: 0 cm; Offset latéral: 0 cm; Décalage supérieur: 0 cm; Décalage inférieur: 0 cm; Nombre accrochages latéraux: 0; Nombre d'accrochages supérieurs: 0; Nombre accrochages inférieurs: 0; IFC_Pset_Géométrie_Niche - Présent: no; Stratigraphie: Paroi en béton armé [120,00]; Épaisseur: 12 cm; Alignement: Intérieur; Décalage: 0 cm; IFC_Pset_Système de Référence Altimétrique_INFÉRIEUR - NIVEAU: Mezzanine (Mezzanine 49003); delta: 166 cm; sous Niveau: <aucun>; IFC_Pset_Données Métré - Surface de l'Ouverture: 3100 cm2; Surface de l'Ébrasement: 0 cm2; Surface du Seuil: 0 cm2; Surface du Seuil intérieur: 0 cm2; Volume du seuil: 0 cm3; Volume du seuil intérieur: 0 cm3; Surface de la Niche: 0 cm2; Surface de la Grille: 0 cm2; Volume de la Grille: 0 cm3
4294966378_11 | Mezzanine | -918 | 2002 | 2002 | 0 | -1292786862
4294966371_11 | Mezzanine | -925 | 2002 | 2002 | 0 | -1292786862
4294966370_11 | Mezzanine | -926 | 2002 | 2002 | 0 | -1292786862
4294966369_11 | Mezzanine | -927 | 2002 | 2002 | 0 | -1292786862
4294966368_11 | Mezzanine | -928 | 2002 | 2002 | 0 | -1292786862
4294966367_11 | Mezzanine | -929 | 2002 | 2002 | 0 | -1292786862
4294966372_11 | Mezzanine | -924 | 2002 | 2002 | 0 | -1292786862
4294966508_11 | Couverture | -788 | 2002 | 2002 | 0 | -1292786862
4294966610 | Couverture | -686 | 2002 | 2002 | 0 | -1292786862
4294966608 | Couverture | -688 | 2002 | 2002 | 0 | -1292786862
4294966507_11 | Couverture | -789 | 2002 | 2002 | 0 | -1292786862
4294966512_11 | Couverture | -784 | 2002 | 2002 | 0 | -1292786862
4294966511_11 | Couverture | -785 | 2002 | 2002 | 0 | -1292786862
4294966506_11 | Couverture | -790 | 2002 | 2002 | 0 | -1292786862
4294966505_11 | Couverture | -791 | 2002 | 2002 | 0 | -1292786862
4294966502_11 | Couverture | -794 | 2002 | 2002 | 0 | -1292786862

# IfcOpeningElement: Recess (35)
CTLG_EXTERNAL_LINK - 0, DocType: 2; 0, Tag: 0
IFC_PSET_PolygonOffset - polygonOffsetFactor: 2; polygonOffsetUnits: 2
Name | In | Description | __RECOGNIZE__, ID | TPLG | TPLG_OD | GENERATE | 0, Crc | 1, DocType | 1, Tag | 1, Crc | IFC_Pset_Caractéristiques, ID | Numérotation | Numéro niveau | Titre niveau | IFC_Pset_Géométrie_Allège, Hauteur (cm) = IFC_Pset_Géométrie_Allège, Épaisseur (cm) = Épaisseur latérale gauche (cm) = Épaisseur latérale droite (cm) = Épiasseur latérale supérieure (cm) = Épaisseur intérieur (cm) = IFC_Pset_Géométrie_Seuil, Épaisseur (cm) = Épaisseur interne (cm) = Décalage séparation (cm) = Appui extérieur (cm) = Appui intérieur (cm) = Côté latéral externe (cm) = Côté latéral interne (cm) = Épaisseur Chambranle intérieur (cm) = Longueur Chambranle intérieur (cm) = Superposition Chambranle intérieur (cm) = Épaisseur Intrados (cm) = Épaisseur Chambranle extérieur (cm) = Largeur Chambranle extérieur (cm) = Superposition Chambranle extérieur (cm) = Épaisseur Intrados extérieur (cm) = Décalage séparation intrados (cm) = IFC_Pset_Géométrie_CORNICHE Extérieure à partir d'un profil, Décalage = IFC_Pset_Géométrie_CORNICHE Extérieure à partir d'un profil, Angle (deg) = IFC_Pset_Géométrie_BASE Extérieure à partir d'un profil, Angle (deg) = Côté (cm) = Hauteur 2 (cm) = Demi-axe horizontal (cm) = Demi-axe vertical (cm) = décalage (cm) = Offset latéral (cm) = Décalage supérieur (cm) = Décalage inférieur (cm) = Nombre accrochages latéraux = Nombre d'accrochages supérieurs = Nombre accrochages inférieurs = IFC_Pset_Géométrie_Niche, Décalage (cm) = Surface du Seuil (cm2) = Surface du Seuil intérieur (cm2) = Volume du seuil (cm3) = Volume du seuil intérieur (cm3) = Surface de la Grille (cm2) = Volume de la Grille (cm3) | IFC_Pset_Géométrie_Allège, Stratigraphie | IFC_Pset_Géométrie_Ébrasement, Présent | Côté supérieur = Côté INFÉRIEUR = IFC_Pset_Géométrie_CORNICHE Extérieure à partir d'un profil, Symétrie = Fermer = IFC_Pset_Géométrie_BASE Extérieure à partir d'un profil, Symétrie | Épaisseur extérieure (cm) | Épaisseur diagonale gauche (cm) = Épaisseur diagonale inférieure (cm) = Épaisseur diagonale supérieure (cm) | Épaisseur diagonale droite (cm) | Type = IFC_Pset_Géométrie_Chambranle, Position | IFC_Pset_Géométrie_CORNICHE depuis profil, Position | IFC_Pset_Géométrie_CORNICHE depuis profil, sets with these values = IFC_Pset_Géométrie_CORNICHE Extérieure à partir d'un profil, sets with these values = IFC_Pset_Géométrie_BASE Extérieure à partir d'un profil, sets with these values | Côté extérieur | Invertir (dte/gche) | Invertir (intérieur/extérieur) | Forme | Largeur (cm) | IFC_Pset_Géométrie, Hauteur (cm) | Rayon Arc (cm) | Rayon Cercle (cm) | IFC_Pset_Géométrie_Niche, Présent | IFC_Pset_Géométrie_Niche, Stratigraphie | IFC_Pset_Géométrie_Niche, Épaisseur (cm) | Alignement | NIVEAU | delta (cm) | sous Niveau | Surface de l'Ouverture (cm2) = Surface de la Niche (cm2) | Surface de l'Ébrasement (cm2)
Baie 1023951 | Default Site | _VTO_Baie | 1023951 | 114 | 9006 | 1 | -746779066 | 9 | 211 | -1269062341 | 1023951 | 163 | 06 | Mezzanine | 0 | ... | yes | no | 20 | 0 | 0 | Aucun | Aucune | 2 | 1 | no | yes | Cercle | 0 | 0 | 0 | 25 | yes | default [200,00] | 20 | Extérieur | Mezzanine (Mezzanine 49003) | 38 | <aucun> | 2000 | 900 | IFC_Pset_Géométrie_Ébrasement - Données: [a : 200,00; b [gche]: 0,00; b [dte]: 0,00; b [sup]: 0,00; c [gche]: 0,00; c [dte]: 0,00; c [inf]: 0,00; c [sup]: 0,00; d: 0,00] mm
Baie 78426 | Rez-de-Jardin | _VTO_Baie | 78426 | 114 | 9006 | 1 | -746779066 | 9 | 211 | -1554559915 | 78426 | 021 | 02 | Rez-de-Jardin | 0 | ... | no | no | 0 | 0 | 0 | Aucun | Aucune | 2 | 0 | no | no | Arc + Rectangle | 110.311 | 113 | 10.2107 | 0 | yes | default [80,00] | 8 | Extérieur | Rez-de-Jardin (Rez-de-Jardin 15545) | 115.102 | <aucun> | 13200 | 0
Baie 361730 | Rez-de-Jardin | _VTO_Baie | 361730 | 114 | 9006 | 1 | -746779066 | 9 | 211 | 1476981794 | 361730 | 055 | 02 | Rez-de-Jardin | 0 | ... | no | no | 0 | 0 | 0 | Aucun | Aucune | 2 | 0 | no | no | Arc + Rectangle | 98.9468 | 80 | 49.4734 | 0 | yes | default [70,00] | 7 | Extérieur | Rez-de-Jardin (Rez-de-Jardin 15545) | 118.707 | <aucun> | 11800 | 0
Baie 78041 | Rez-de-Jardin | _VTO_Baie | 78041 | 114 | 9006 | 1 | -746779066 | 9 | 211 | 1510621264 | 78041 | 020 | 02 | Rez-de-Jardin | 0 | ... | no | no | 0 | 0 | 0 | Aucun | Aucune | 2 | 1 | no | no | Arc + Rectangle | 84.9189 | 218.694 | 5 | 0 | yes | default [390,00] | 39 | Intérieur | Rez-de-Jardin (Rez-de-Jardin 15545) | 1 | <aucun> | 18800 | 0
Baie 379793 | Rez-de-chaussée | _VTO_Baie | 379793 | 114 | 9006 | 1 | -746779066 | 9 | 211 | -1554559915 | 379793 | 079 | 03 | Rez-de-chaussée | 0 | ... | no | no | 0 | 0 | 0 | Aucun | Aucune | 2 | 0 | no | no | Rectangle | 132.029 | 261 | 0 | 0 | yes | default [80,00] | 8 | Extérieur | Rez-de-chaussée (Rez-de-chaussée 1047) | 0.0128504 | <aucun> | 34500 | 0
Baie 30045 | Rez-de-chaussée | _VTO_Baie | 30045 | 114 | 9006 | 1 | -746779066 | 9 | 211 | -1554559915 | 30045 | 012 | 03 | Rez-de-chaussée | 0 | ... | no | no | 0 | 0 | 0 | Aucun | Aucune | 2 | 0 | no | no | Rectangle | 122 | 50 | 0 | 0 | yes | default [80,00] | 8 | Extérieur | Rez-de-chaussée (Rez-de-chaussée 1047) | 0.0128504 | <aucun> | 6100 | 0
Baie 30038 | Rez-de-chaussée | _VTO_Baie | 30038 | 114 | 9006 | 1 | -746779066 | 9 | 211 | -1554559915 | 30038 | 008 | 03 | Rez-de-chaussée | 0 | ... | no | no | 0 | 0 | 0 | Aucun | Aucune | 2 | 0 | no | no | Rectangle | 129.157 | 48.5 | 0 | 0 | yes | default [80,00] | 8 | Extérieur | Rez-de-chaussée (Rez-de-chaussée 1047) | 0.0128504 | <aucun> | 6300 | 0
Baie 30044 | Rez-de-chaussée | _VTO_Baie | 30044 | 114 | 9006 | 1 | -746779066 | 9 | 211 | -1554559915 | 30044 | 011 | 03 | Rez-de-chaussée | 0 | ... | no | no | 0 | 0 | 0 | Aucun | Aucune | 2 | 0 | no | no | Rectangle | 127.26 | 49.5 | 0 | 0 | yes | default [80,00] | 8 | Extérieur | Rez-de-chaussée (Rez-de-chaussée 1047) | 0.0128504 | <aucun> | 6300 | 0
Baie 23852 | Rez-de-chaussée | _VTO_Baie | 23852 | 114 | 9006 | 1 | -746779066 | 9 | 211 | -1554559915 | 23852 | 002 | 03 | Rez-de-chaussée | 0 | ... | no | no | 0 | 0 | 0 | Aucun | Aucune | 2 | 0 | no | no | Rectangle | 139.98 | 48 | 0 | 0 | yes | default [80,00] | 8 | Extérieur | Rez-de-chaussée (Rez-de-chaussée 1047) | 0.0128504 | <aucun> | 6700 | 0
Baie 23855 | Rez-de-chaussée | _VTO_Baie | 23855 | 114 | 9006 | 1 | -746779066 | 9 | 211 | -1554559915 | 23855 | 003 | 03 | Rez-de-chaussée | 0 | ... | no | no | 0 | 0 | 0 | Aucun | Aucune | 2 | 0 | no | no | Rectangle | 127.8 | 49 | 0 | 0 | yes | default [80,00] | 8 | Extérieur | Rez-de-chaussée (Rez-de-chaussée 1047) | 0.0128504 | <aucun> | 6300 | 0
Baie 23835 | Rez-de-chaussée | _VTO_Baie | 23835 | 114 | 9006 | 1 | -746779066 | 9 | 211 | -1554559915 | 23835 | 001 | 03 | Rez-de-chaussée | 0 | ... | no | no | 0 | 0 | 0 | Aucun | Aucune | 2 | 1 | no | no | Rectangle | 126.235 | 51 | 0 | 0 | yes | default [80,00] | 8 | Extérieur | Rez-de-chaussée (Rez-de-chaussée 1047) | 0.0128504 | <aucun> | 6400 | 0
Baie 30039 | Rez-de-chaussée | _VTO_Baie | 30039 | 114 | 9006 | 1 | -746779066 | 9 | 211 | -1554559915 | 30039 | 009 | 03 | Rez-de-chaussée | 0 | ... | no | no | 0 | 0 | 0 | Aucun | Aucune | 2 | 0 | no | no | Rectangle | 198 | 48.5 | 0 | 0 | yes | default [80,00] | 8 | Extérieur | Rez-de-chaussée (Rez-de-chaussée 1047) | 0.0128504 | <aucun> | 9600 | 0
Baie 30040 | Rez-de-chaussée | _VTO_Baie | 30040 | 114 | 9006 | 1 | -746779066 | 9 | 211 | -1554559915 | 30040 | 010 | 03 | Rez-de-chaussée | 0 | ... | no | no | 0 | 0 | 0 | Aucun | Aucune | 2 | 0 | no | no | Rectangle | 121.149 | 48.5 | 0 | 0 | yes | default [80,00] | 8 | Extérieur | Rez-de-chaussée (Rez-de-chaussée 1047) | 0.0128504 | <aucun> | 5900 | 0
Baie 41618 | Rez-de-chaussée | _VTO_Baie | 41618 | 114 | 9006 | 1 | -746779066 | 9 | 211 | -1554559915 | 41618 | 016 | 03 | Rez-de-chaussée | 0 | ... | no | no | 0 | 0 | 0 | Aucun | Aucune | 2 | 1 | no | no | Rectangle | 133.151 | 43 | 0 | 0 | yes | default [80,00] | 8 | Extérieur | Rez-de-chaussée (Rez-de-chaussée 1047) | 0.0128504 | <aucun> | 5700 | 0
Baie 41617 | Rez-de-chaussée | _VTO_Baie | 41617 | 114 | 9006 | 1 | -746779066 | 9 | 211 | -1554559915 | 41617 | 015 | 03 | Rez-de-chaussée | 0 | ... | no | no | 0 | 0 | 0 | Aucun | Aucune | 2 | 1 | no | no | Rectangle | 126 | 54.9 | 0 | 0 | yes | default [80,00] | 8 | Extérieur | Rez-de-chaussée (Rez-de-chaussée 1047) | 0.0128504 | <aucun> | 6900 | 0
Baie 24222 | Rez-de-chaussée | _VTO_Baie | 24222 | 114 | 9006 | 1 | -746779066 | 9 | 211 | 1582870039 | 24222 | 004 | 03 | Rez-de-chaussée | 0 | ... | no | no | 0 | 0 | 0 | Aucun | Aucune | 2 | 0 | no | no | Rectangle | 130.802 | 151 | 0 | 0 | yes | default [210,00] | 21 | Intérieur | Rez-de-chaussée (Rez-de-chaussée 1047) | 117.259 | <aucun> | 19800 | 0
Baie 41485 | Rez-de-chaussée | _VTO_Baie | 41485 | 114 | 9006 | 1 | -746779066 | 9 | 211 | 624124834 | 41485 | 013 | 03 | Rez-de-chaussée | 0 | ... | yes | no | 12 | 5 | 5 | Aucun | Aucune | 2 | 1 | no | no | Rectangle | 126.72 | 54.5 | 0 | 0 | yes | default [120,00] | 12 | Extérieur | Rez-de-chaussée (Rez-de-chaussée 1047) | 0.0128504 | <aucun> | 6900 | 2300 | IFC_Pset_Géométrie_Ébrasement - Données: [a : 120,00; b: 0,00; c: 50,00; d: 0,00] mm
Baie 41487 | Rez-de-chaussée | _VTO_Baie | 41487 | 114 | 9006 | 1 | -746779066 | 9 | 211 | 2019374073 | 41487 | 014 | 03 | Rez-de-chaussée | 0 | ... | yes | no | 13 | 4 | 5 | Aucun | Aucune | 2 | 1 | no | no | Rectangle | 125 | 54.5 | 0 | 0 | yes | default [130,00] | 13 | Extérieur | Rez-de-chaussée (Rez-de-chaussée 1047) | 0.0128504 | <aucun> | 6800 | 3200 | IFC_Pset_Géométrie_Ébrasement - Données: [a : 130,00; b: 0,00; c: 40,00; d: 0,00] mm
Baie 103169 | Niveau 1 | _VTO_Baie | 103169 | 114 | 9006 | 1 | -746779066 | 9 | 211 | -1554559915 | 103169 | 029 | 04 | Niveau 1 | 0 | ... | no | no | 0 | 0 | 0 | Aucun | Aucune | 2 | 1 | no | no | Rectangle | 109.113 | 53.9 | 0 | 0 | yes | default [80,00] | 8 | Extérieur | Niveau 1 (Niveau 1 2343) | 0.0128504 | <aucun> | 5900 | 0
Baie 103653 | Niveau 1 | _VTO_Baie | 103653 | 114 | 9006 | 1 | -746779066 | 9 | 211 | -1554559915 | 103653 | 033 | 04 | Niveau 1 | 0 | ... | no | no | 0 | 0 | 0 | Aucun | Aucune | 2 | 0 | no | no | Rectangle | 107.643 | 61 | 0 | 0 | yes | default [80,00] | 8 | Extérieur | Niveau 1 (Niveau 1 2343) | 0.0128504 | <aucun> | 6600 | 0
Baie 115414 | Niveau 1 | _VTO_Baie | 115414 | 114 | 9006 | 1 | -746779066 | 9 | 211 | -1554559915 | 115414 | 035 | 04 | Niveau 1 | 0 | ... | no | no | 0 | 0 | 0 | Aucun | Aucune | 2 | 0 | no | no | Rectangle | 109.068 | 52.5 | 0 | 0 | yes | default [80,00] | 8 | Extérieur | Niveau 1 (Niveau 1 2343) | 0.0128504 | <aucun> | 5700 | 0
Baie 103201 | Niveau 1 | _VTO_Baie | 103201 | 114 | 9006 | 1 | -746779066 | 9 | 211 | -1554559915 | 103201 | 030 | 04 | Niveau 1 | 0 | ... | no | no | 0 | 0 | 0 | Aucun | Aucune | 2 | 0 | no | no | Rectangle | 108.569 | 53 | 0 | 0 | yes | default [80,00] | 8 | Extérieur | Niveau 1 (Niveau 1 2343) | 0.0128504 | <aucun> | 5800 | 0
Baie 115411 | Niveau 1 | _VTO_Baie | 115411 | 114 | 9006 | 1 | -746779066 | 9 | 211 | -1554559915 | 115411 | 034 | 04 | Niveau 1 | 0 | ... | no | no | 0 | 0 | 0 | Aucun | Aucune | 2 | 0 | no | no | Rectangle | 116.32 | 54 | 0 | 0 | yes | default [80,00] | 8 | Extérieur | Niveau 1 (Niveau 1 2343) | 0.0128504 | <aucun> | 6300 | 0
Baie 120793 | Niveau 1 | _VTO_Baie | 120793 | 114 | 9006 | 1 | -746779066 | 9 | 211 | 1476981794 | 120793 | 039 | 04 | Niveau 1 | 0 | ... | yes | no | 7 | 2 | 2 | Aucun | Aucune | 2 | 1 | no | no | Rectangle | 109.177 | 289 | 0 | 0 | yes | default [70,00] | 7 | Extérieur | Niveau 1 (Niveau 1 2343) | 0.0128504 | <aucun> | 31600 | 19100 | IFC_Pset_Géométrie_Ébrasement - Données: [a : 70,00; b: 0,00; c: 20,00; d: 0,00] mm
Baie 103161 | Niveau 1 | _VTO_Baie | 103161 | 114 | 9006 | 1 | -746779066 | 9 | 211 | -1554559915 | 103161 | 028 | 04 | Niveau 1 | 0 | ... | no | no | 0 | 0 | 0 | Aucun | Aucune | 2 | 0 | no | no | Rectangle | 109.572 | 52.5 | 0 | 0 | yes | default [80,00] | 8 | Extérieur | Niveau 1 (Niveau 1 2343) | 0.0556206 | <aucun> | 5800 | 0
Baie 103207 | Niveau 1 | _VTO_Baie | 103207 | 114 | 9006 | 1 | -746779066 | 9 | 211 | -1554559915 | 103207 | 032 | 04 | Niveau 1 | 0 | ... | no | no | 0 | 0 | 0 | Aucun | Aucune | 2 | 0 | no | no | Rectangle | 69.309 | 54 | 0 | 0 | yes | default [80,00] | 8 | Extérieur | Niveau 1 (Niveau 1 2343) | 0.0128504 | <aucun> | 3700 | 0
Baie 103204 | Niveau 1 | _VTO_Baie | 103204 | 114 | 9006 | 1 | -746779066 | 9 | 211 | -1554559915 | 103204 | 031 | 04 | Niveau 1 | 0 | ... | no | no | 0 | 0 | 0 | Aucun | Aucune | 2 | 0 | yes | no | Rectangle | 67.1698 | 53 | 0 | 0 | yes | default [80,00] | 8 | Extérieur | Niveau 1 (Niveau 1 2343) | 0.0128504 | <aucun> | 3600 | 0
4294966556_12 | Niveau 1 |  | -740 | 2002 | 2002 | 0 | -1292786862
Baie 1295380 | Mezzanine | _VTO_Baie | 1295380 | 114 | 9006 | 1 | -746779066 | 9 | 211 | -1269062341 | 1295380 | 167 | 06 | Mezzanine | 0 | ... | yes | no | 20 | 0 | 0 | Aucun | Aucune | 2 | 0 | no | no | Cercle | 0 | 0 | 0 | 25 | yes | default [200,00] | 20 | Extérieur | Mezzanine (Mezzanine 49003) | 57.9806 | <aucun> | 2000 | 900 | IFC_Pset_Géométrie_Ébrasement - Données: [a : 200,00; b [gche]: 0,00; b [dte]: 0,00; b [sup]: 0,00; c [gche]: 0,00; c [dte]: 0,00; c [inf]: 0,00; c [sup]: 0,00; d: 0,00] mm
Baie 1168234 | Mezzanine | _VTO_Baie | 1168234 | 114 | 9006 | 1 | -746779066 | 9 | 211 | -1269062341 | 1168234 | 166 | 06 | Mezzanine | 0 | ... | yes | no | 20 | 0 | 0 | Aucun | Aucune | 2 | 0 | no | no | Cercle | 0 | 0 | 0 | 35 | yes | default [200,00] | 20 | Extérieur | Mezzanine (Mezzanine 49003) | 47 | <aucun> | 3800 | 1300 | IFC_Pset_Géométrie_Ébrasement - Données: [a : 200,00; b [gche]: 0,00; b [dte]: 0,00; b [sup]: 0,00; c [gche]: 0,00; c [dte]: 0,00; c [inf]: 0,00; c [sup]: 0,00; d: 0,00] mm
Baie 1018897 | Mezzanine | _VTO_Baie | 1018897 | 114 | 9006 | 1 | -746779066 | 9 | 211 | -1269062341 | 1018897 | 160 | 06 | Mezzanine | 0 | ... | yes | no | 20 | 0 | 0 | Aucun | Aucune | 2 | 0 | no | no | Cercle | 0 | 0 | 0 | 25 | yes | default [200,00] | 20 | Extérieur | Mezzanine (Mezzanine 49003) | 37.0017 | <aucun> | 2000 | 900 | IFC_Pset_Géométrie_Ébrasement - Données: [a : 200,00; b [gche]: 0,00; b [dte]: 0,00; b [sup]: 0,00; c [gche]: 0,00; c [dte]: 0,00; c [inf]: 0,00; c [sup]: 0,00; d: 0,00] mm
Baie 1020633 | Mezzanine | _VTO_Baie | 1020633 | 114 | 9006 | 1 | -746779066 | 9 | 211 | -1269062341 | 1020633 | 162 | 06 | Mezzanine | 0 | ... | no | no | 0 | 0 | 0 | Aucun | Aucune | 2 | 0 | no | no | Cercle | 0 | 0 | 0 | 30 | yes | default [200,00] | 20 | Extérieur | Mezzanine (Mezzanine 49003) | 37 | <aucun> | 2800 | 0
Baie 1018902 | Mezzanine | _VTO_Baie | 1018902 | 114 | 9006 | 1 | -746779066 | 9 | 211 | -1269062341 | 1018902 | 161 | 06 | Mezzanine | 0 | ... | yes | no | 20 | 0 | 0 | Aucun | Aucune | 2 | 0 | no | no | Cercle | 0 | 0 | 0 | 30 | yes | default [200,00] | 20 | Extérieur | Mezzanine (Mezzanine 49003) | 53 | <aucun> | 2800 | 1100 | IFC_Pset_Géométrie_Ébrasement - Données: [a : 200,00; b [gche]: 0,00; b [dte]: 0,00; b [sup]: 0,00; c [gche]: 0,00; c [dte]: 0,00; c [inf]: 0,00; c [sup]: 0,00; d: 0,00] mm
Baie 1149552 | Mezzanine | _VTO_Baie | 1149552 | 114 | 9006 | 1 | -746779066 | 9 | 211 | -1269062341 | 1149552 | 165 | 06 | Mezzanine | 0 | ... | yes | no | 20 | 0 | 0 | Aucun | Aucune | 2 | 0 | no | no | Cercle | 0 | 0 | 0 | 25 | yes | default [200,00] | 20 | Extérieur | Mezzanine (Mezzanine 49003) | 40.9816 | <aucun> | 2000 | 900 | IFC_Pset_Géométrie_Ébrasement - Données: [a : 200,00; b [gche]: 0,00; b [dte]: 0,00; b [sup]: 0,00; c [gche]: 0,00; c [dte]: 0,00; c [inf]: 0,00; c [sup]: 0,00; d: 0,00] mm
Baie 1030972 | Mezzanine | _VTO_Baie | 1030972 | 114 | 9006 | 1 | -746779066 | 9 | 211 | -1269062341 | 1030972 | 164 | 06 | Mezzanine | 0 | ... | yes | no | 20 | 0 | 0 | Aucun | Aucune | 2 | 1 | no | yes | Cercle | 0 | 0 | 0 | 25 | yes | default [200,00] | 20 | Extérieur | Mezzanine (Mezzanine 49003) | 39.6411 | <aucun> | 2000 | 900 | IFC_Pset_Géométrie_Ébrasement - Données: [a : 200,00; b [gche]: 0,00; b [dte]: 0,00; b [sup]: 0,00; c [gche]: 0,00; c [dte]: 0,00; c [inf]: 0,00; c [sup]: 0,00; d: 0,00] mm

# IfcPlate (49)
__RECOGNIZE__ - TPLG: 2002; TPLG_OD: 2002; GENERATE: 0
Name | In | Material | ID | Reference
4294967254 | Rez-de-Jardin | Aluminium mat | -42 | Panneau
4294967253 | Rez-de-Jardin | Aluminium mat | -43 | Panneau
4294967234 | Rez-de-Jardin | Aluminium mat | -62 | Panneau
4294967154 | Rez-de-Jardin | Teck | -142 | Panneau
4294966833 | Rez-de-Jardin | Orme | -463 | Panneau
4294966756 | Rez-de-Jardin | Orme | -540 | Panneau
4294967233 | Rez-de-chaussée | Aluminium mat | -63 | Panneau
4294967230 | Rez-de-chaussée | Aluminium mat | -66 | Panneau
4294967229 | Rez-de-chaussée | Aluminium mat | -67 | Panneau
4294967232 | Niveau 1 | Aluminium mat | -64 | Panneau
4294967231 | Niveau 1 | Aluminium mat | -65 | Panneau
4294967021 | Niveau 1 | Aluminium mat | -275 | Panneau
4294967023 | Niveau 2 | Aluminium mat | -273 | Panneau
4294967022 | Niveau 2 | Aluminium mat | -274 | Panneau
4294967020 | Niveau 2 | Aluminium mat | -276 | Panneau
4294967210 | Couverture | Transparent | -86 | Vitre
4294967208 | Couverture | Transparent | -88 | Vitre
4294967206 | Couverture | Transparent | -90 | Vitre
4294967204 | Couverture | Transparent | -92 | Vitre
4294967202 | Couverture | Transparent | -94 | Vitre
4294967200 | Couverture | Transparent | -96 | Vitre
4294967198 | Couverture | Transparent | -98 | Vitre
4294967196 | Couverture | Transparent | -100 | Vitre
4294967194 | Couverture | Transparent | -102 | Vitre
4294967017 | Couverture | Transparent | -279 | Vitre
4294967014 | Couverture | Transparent | -282 | Vitre
4294967011 | Couverture | Transparent | -285 | Vitre
4294967008 | Couverture | Transparent | -288 | Vitre
4294967005 | Couverture | Transparent | -291 | Vitre
4294967003 | Couverture | Transparent | -293 | Vitre
4294966905 | Couverture | Transparent | -391 | Vitre
4294966903 | Couverture | Transparent | -393 | Vitre
4294966671 | Couverture | Transparent | -625 | Vitre
4294966669 | Couverture | Transparent | -627 | Vitre
4294966667 | Couverture | Transparent | -629 | Vitre
4294966665 | Couverture | Transparent | -631 | Vitre
4294966663 | Couverture | Transparent | -633 | Vitre
4294966661 | Couverture | Transparent | -635 | Vitre
4294966659 | Couverture | Transparent | -637 | Vitre
4294966657 | Couverture | Transparent | -639 | Vitre
4294966655 | Couverture | Transparent | -641 | Vitre
4294966653 | Couverture | Transparent | -643 | Vitre
4294966651 | Couverture | Transparent | -645 | Vitre
4294966649 | Couverture | Transparent | -647 | Vitre
4294966647 | Couverture | Transparent | -649 | Vitre
4294966645 | Couverture | Transparent | -651 | Vitre
4294966643 | Couverture | Transparent | -653 | Vitre
4294966641 | Couverture | Transparent | -655 | Vitre
4294966639 | Couverture | Transparent | -657 | Vitre

# IfcRailing: Balaustra [AV] elementi tondi (5)
In: Mezzanine
Type - Material: Jaune 255-255-0
Description: Garde-corps; Group: ...de garde-corps = Balaustra [AV] elementi tondi; ...de matériaux et couleurs = Jaune 255-255-0; ...de matériaux et couleurs - 1 = Jaune 255-255-0; ...de matériaux et couleurs - 2 = Jaune 255-255-0; ...de matériaux et couleurs - 3 = Jaune 255-255-0
__RECOGNIZE__ - TPLG: 141; TPLG_OD: 141; GENERATE: 1
CTLG_EXTERNAL_LINK - 0, DocType: 4; 0, Tag: 4000; 0, Crc: 622452120; 1, DocType: 2; 1, Tag: 0; 1, Crc: -799740758; 2, DocType: 2; 2, Tag: 1; 2, Crc: -799740758; 3, DocType: 2; 3, Tag: 2; 3, Crc: -799740758; 4, DocType: 2; 4, Tag: 3; 4, Crc: -799740758
IFC_PSET_PolygonOffset - polygonOffsetFactor: 2; polygonOffsetUnits: 2
IFC_Pset_Caractéristiques - Numéro niveau: 06; Titre niveau: Mezzanine
IFC_Pset_Géométrie - Modèle: Balaustra [AV] elementi tondi; Hauteur: 100 cm
IFC_Pset_Géométrie_DÉCALAGE - initial: 0 cm; final: 0 cm; latéral: 0 cm
IFC_Pset_Système de Référence Altimétrique_INFÉRIEUR - NIVEAU: Mezzanine (Mezzanine 49003)
IFC_Pset_Matériaux - Principal: Jaune 255-255-0; Matériau (2): Jaune 255-255-0; Matériau (3): Jaune 255-255-0; Matériau (4): Jaune 255-255-0
Pset_RailingCommon - Reference: Balaustra [AV] elementi tondi (..\Garde-corps et parapets\); Height: 100 cm
Name | __RECOGNIZE__, ID = IFC_Pset_Caractéristiques, ID | Numérotation | Longueur (cm) | Surface peinturable (totale) (cm2) | Surface (Longueur x Hauteur) (cm2) | delta (cm)
Garde-corps 192721 | 192721 | 14 | 527.706 | 34484 | 52770.6 | 45
Garde-corps 192921 | 192921 | 15 | 204.324 | 13827.8 | 20432.4 | 45
Garde-corps 222215 | 222215 | 18 | 102.806 | 7301.63 | 10280.6 | 1.5
Garde-corps 222868 | 222868 | 19 | 136.964 | 9481.04 | 13696.4 | 0
Garde-corps 223120 | 223120 | 20 | 111.996 | 8000.53 | 11199.6 | 0

# IfcRailing: Balustrade [FV] (2)
In: Niveau 1
Type - Material: Fer, Aluminium mat
Description: Garde-corps; Group: ...de matériaux et couleurs - 1 = Aluminium mat; ...de matériaux et couleurs - 2 = Aluminium mat; ...de matériaux et couleurs - 3 = Aluminium mat; ...de matériaux et couleurs = Fer; ...de garde-corps = Balustrade [FV]
__RECOGNIZE__ - TPLG: 141; TPLG_OD: 141; GENERATE: 1
CTLG_EXTERNAL_LINK - 0, DocType: 4; 0, Tag: 4000; 0, Crc: -820376445; 1, DocType: 2; 1, Tag: 0; 1, Crc: 528919847; 2, DocType: 2; 2, Tag: 1; 2, Crc: 913068333; 3, DocType: 2; 3, Tag: 2; 3, Crc: 913068333; 4, DocType: 2; 4, Tag: 3; 4, Crc: 913068333
IFC_PSET_PolygonOffset - polygonOffsetFactor: 2; polygonOffsetUnits: 2
IFC_Pset_Caractéristiques - Numéro niveau: 04; Titre niveau: Niveau 1
IFC_Pset_Géométrie - Modèle: Balustrade [FV]; Hauteur: 115.9 cm
IFC_Pset_Géométrie_DÉCALAGE - initial: 0 cm; final: 0 cm; latéral: 0 cm
IFC_Pset_Système de Référence Altimétrique_INFÉRIEUR - NIVEAU: Niveau 1 (Niveau 1 2343); delta: 165.6 cm
IFC_Pset_Matériaux - Principal: Fer; Matériau (2): Aluminium mat; Matériau (3): Aluminium mat; Matériau (4): Aluminium mat
Pset_RailingCommon - Reference: Balustrade [FV] (..\Garde-corps et parapets sur mur\); Height: 100 cm
Name | __RECOGNIZE__, ID = IFC_Pset_Caractéristiques, ID | Numérotation | Longueur (cm) | Surface peinturable (totale) (cm2) | Surface (Longueur x Hauteur) (cm2)
Garde-corps 133768 | 133768 | 06 | 94.3216 | 9660.32 | 10931.9
Garde-corps 133767 | 133767 | 05 | 93.1203 | 9629.08 | 10792.6

# IfcRailing: Barreaux en bois avec poteaux pointus (2)
In: Mezzanine
Type - Material: Jaune 255-255-0
Description: Garde-corps; Group: ...de matériaux et couleurs = Jaune 255-255-0; ...de matériaux et couleurs - 1 = Jaune 255-255-0; ...de matériaux et couleurs - 2 = Jaune 255-255-0; ...de matériaux et couleurs - 3 = Jaune 255-255-0; ...de garde-corps = Barreaux en bois avec poteaux pointus
__RECOGNIZE__ - TPLG: 141; TPLG_OD: 141; GENERATE: 1
CTLG_EXTERNAL_LINK - 0, DocType: 4; 0, Tag: 4000; 0, Crc: 1356232909; 1, DocType: 2; 1, Tag: 0; 1, Crc: -799740758; 2, DocType: 2; 2, Tag: 1; 2, Crc: -799740758; 3, DocType: 2; 3, Tag: 2; 3, Crc: -799740758; 4, DocType: 2; 4, Tag: 3; 4, Crc: -799740758
IFC_PSET_PolygonOffset - polygonOffsetFactor: 2; polygonOffsetUnits: 2
IFC_Pset_Caractéristiques - Numéro niveau: 06; Titre niveau: Mezzanine
IFC_Pset_Géométrie - Modèle: Barreaux en bois avec poteaux pointus; Hauteur: 115 cm
IFC_Pset_Géométrie_DÉCALAGE - initial: 0 cm; final: 0 cm; latéral: 0 cm
IFC_Pset_Système de Référence Altimétrique_INFÉRIEUR - NIVEAU: Mezzanine (Mezzanine 49003); delta: 58 cm
IFC_Pset_Matériaux - Principal: Jaune 255-255-0; Matériau (2): Jaune 255-255-0; Matériau (3): Jaune 255-255-0; Matériau (4): Jaune 255-255-0
Pset_RailingCommon - Reference: Barreaux en bois avec poteaux pointus (..\Clôtures\); Height: 100 cm
Name | __RECOGNIZE__, ID = IFC_Pset_Caractéristiques, ID | Numérotation | Longueur (cm) | Surface peinturable (totale) (cm2) | Surface (Longueur x Hauteur) (cm2)
Garde-corps 198413 | 198413 | 17 | 22.15 | 12088.3 | 2547.25
Garde-corps 195654 | 195654 | 16 | 145.801 | 45919.8 | 16767.1

# IfcRailing: Colonnes rectangulaire (4)
Type - Material: Pierre du saint gottard, Aluminium mat
Description: Garde-corps; Group: ...de matériaux et couleurs - 1 = Aluminium mat; ...de matériaux et couleurs - 2 = Aluminium mat; ...de matériaux et couleurs - 3 = Aluminium mat; ...de garde-corps = Colonnes rectangulaire; ...de matériaux et couleurs = Pierre du saint gottard
__RECOGNIZE__ - TPLG: 141; TPLG_OD: 141; GENERATE: 1
CTLG_EXTERNAL_LINK - 0, DocType: 4; 0, Tag: 4000; 0, Crc: 928944458; 1, DocType: 2; 1, Tag: 0; 1, Crc: 496042144; 2, DocType: 2; 2, Tag: 1; 2, Crc: 913068333; 3, DocType: 2; 3, Tag: 2; 3, Crc: 913068333; 4, DocType: 2; 4, Tag: 3; 4, Crc: 913068333
IFC_PSET_PolygonOffset - polygonOffsetFactor: 2; polygonOffsetUnits: 2
IFC_Pset_Géométrie - Modèle: Colonnes rectangulaire; Hauteur: 60 cm
IFC_Pset_Géométrie_DÉCALAGE - initial: 0 cm; final: 0 cm; latéral: 0 cm
IFC_Pset_Matériaux - Principal: Pierre du saint gottard; Matériau (2): Aluminium mat; Matériau (3): Aluminium mat; Matériau (4): Aluminium mat
Pset_RailingCommon - Reference: Colonnes rectangulaire (..\Balustrades sur mur\); Height: 100 cm
Name | In | __RECOGNIZE__, ID = IFC_Pset_Caractéristiques, ID | Numérotation | Numéro niveau | Titre niveau | Longueur (cm) | Surface peinturable (totale) (cm2) | Surface (Longueur x Hauteur) (cm2) | NIVEAU | delta (cm)
Garde-corps 322635 | Rez-de-Jardin | 322635 | 26 | 02 | Rez-de-Jardin | 91.0177 | 19807.1 | 5461.06 | Rez-de-Jardin (Rez-de-Jardin 15545) | 203
Garde-corps 326483 | Rez-de-Jardin | 326483 | 27 | 02 | Rez-de-Jardin | 89.7978 | 19680.3 | 5387.87 | Rez-de-Jardin (Rez-de-Jardin 15545) | 200
Garde-corps 379474 | Rez-de-chaussée | 379474 | 30 | 03 | Rez-de-chaussée | 159.551 | 35214.6 | 9573.06 | Rez-de-chaussée (Rez-de-chaussée 1047) | -2
Garde-corps 379473 | Rez-de-chaussée | 379473 | 29 | 03 | Rez-de-chaussée | 159.129 | 35170.5 | 9547.73 | Rez-de-chaussée (Rez-de-chaussée 1047) | -2

# IfcRailing: Colonnes à deux ventres (2)
Type - Material: Noyer 01, Aluminium mat
Description: Garde-corps; Group: ...de matériaux et couleurs - 1 = Aluminium mat; ...de matériaux et couleurs - 2 = Aluminium mat; ...de matériaux et couleurs - 3 = Aluminium mat; ...de garde-corps = Colonnes à deux ventres; ...de matériaux et couleurs = Noyer 01
__RECOGNIZE__ - TPLG: 141; TPLG_OD: 141; GENERATE: 1
CTLG_EXTERNAL_LINK - 0, DocType: 4; 0, Tag: 4000; 0, Crc: 567235520; 1, DocType: 2; 1, Tag: 0; 1, Crc: -453346083; 2, DocType: 2; 2, Tag: 1; 2, Crc: 913068333; 3, DocType: 2; 3, Tag: 2; 3, Crc: 913068333; 4, DocType: 2; 4, Tag: 3; 4, Crc: 913068333
IFC_PSET_PolygonOffset - polygonOffsetFactor: 2; polygonOffsetUnits: 2
IFC_Pset_Géométrie - Modèle: Colonnes à deux ventres; Hauteur: 100 cm
IFC_Pset_Géométrie_DÉCALAGE - initial: 0 cm; final: 0 cm; latéral: 0 cm
IFC_Pset_Système de Référence Altimétrique_INFÉRIEUR - delta: 0 cm
IFC_Pset_Matériaux - Principal: Noyer 01; Matériau (2): Aluminium mat; Matériau (3): Aluminium mat; Matériau (4): Aluminium mat
Pset_RailingCommon - Reference: Colonnes à deux ventres (..\Balustrades\); Height: 100 cm
Name | In | __RECOGNIZE__, ID = IFC_Pset_Caractéristiques, ID | Numérotation | Numéro niveau | Titre niveau | Longueur (cm) | Surface peinturable (totale) (cm2) | Surface (Longueur x Hauteur) (cm2) | NIVEAU
Garde-corps 133882 | Rez-de-chaussée | 133882 | 08 | 03 | Rez-de-chaussée | 702.226 | 247902 | 70222.6 | Rez-de-chaussée (Rez-de-chaussée 1047)
Garde-corps 133881 | Niveau 1 | 133881 | 07 | 04 | Niveau 1 | 976.674 | 330236 | 97667.4 | Niveau 1 (Niveau 1 2343)

# IfcRailing: Double poteau [FV] (3)
In: Rez-de-Jardin
Type - Material: Aluminium satiné, Aluminium mat
Description: Garde-corps; Group: ...de matériaux et couleurs = Aluminium satiné; ...de matériaux et couleurs - 1 = Aluminium mat; ...de matériaux et couleurs - 2 = Aluminium mat; ...de matériaux et couleurs - 3 = Aluminium mat; ...de garde-corps = Double poteau [FV]
__RECOGNIZE__ - TPLG: 141; TPLG_OD: 141; GENERATE: 1
CTLG_EXTERNAL_LINK - 0, DocType: 4; 0, Tag: 4000; 0, Crc: 481760863; 1, DocType: 2; 1, Tag: 0; 1, Crc: 1305662025; 2, DocType: 2; 2, Tag: 1; 2, Crc: 913068333; 3, DocType: 2; 3, Tag: 2; 3, Crc: 913068333; 4, DocType: 2; 4, Tag: 3; 4, Crc: 913068333
IFC_PSET_PolygonOffset - polygonOffsetFactor: 2; polygonOffsetUnits: 2
IFC_Pset_Caractéristiques - Numéro niveau: 02; Titre niveau: Rez-de-Jardin
IFC_Pset_Géométrie - Modèle: Double poteau [FV]; Hauteur: 50 cm
IFC_Pset_Géométrie_DÉCALAGE - initial: 0 cm; final: 0 cm; latéral: 0 cm
IFC_Pset_Système de Référence Altimétrique_INFÉRIEUR - NIVEAU: Rez-de-Jardin (Rez-de-Jardin 15545)
IFC_Pset_Matériaux - Principal: Aluminium satiné; Matériau (2): Aluminium mat; Matériau (3): Aluminium mat; Matériau (4): Aluminium mat
Pset_RailingCommon - Reference: Double poteau [FV] (..\Garde-corps et parapets sur mur\); Height: 100 cm
Name | __RECOGNIZE__, ID = IFC_Pset_Caractéristiques, ID | Numérotation | Longueur (cm) | Surface peinturable (totale) (cm2) | Surface (Longueur x Hauteur) (cm2) | delta (cm)
Garde-corps 149752 | 149752 | 11 | 849.203 | 11952.7 | 42460.1 | 210
Garde-corps 303638 | 303638 | 25 | 404.163 | 6053.58 | 20208.2 | 160
Garde-corps 350884 | 350884 | 28 | 307.563 | 5155.29 | 15378.2 | 160

# IfcRailing: Double poteau [FV], Garde-corps 73500
In: Rez-de-Jardin
Type - Material: Beige
Description: Garde-corps; Group: ...de garde-corps = Double poteau [FV]; ...de matériaux et couleurs = Beige; ...de matériaux et couleurs - 1 = Beige; ...de matériaux et couleurs - 2 = Beige; ...de matériaux et couleurs - 3 = Beige
__RECOGNIZE__ - ID: 73500; TPLG: 141; TPLG_OD: 141; GENERATE: 1
CTLG_EXTERNAL_LINK - 0, DocType: 4; 0, Tag: 4000; 0, Crc: 481760863; 1, DocType: 2; 1, Tag: 0; 1, Crc: 2035114887; 2, DocType: 2; 2, Tag: 1; 2, Crc: 2035114887; 3, DocType: 2; 3, Tag: 2; 3, Crc: 2035114887; 4, DocType: 2; 4, Tag: 3; 4, Crc: 2035114887
IFC_PSET_PolygonOffset - polygonOffsetFactor: 2; polygonOffsetUnits: 2
IFC_Pset_Caractéristiques - ID: 73500; Numérotation: 02; Numéro niveau: 02; Titre niveau: Rez-de-Jardin
IFC_Pset_Géométrie - Modèle: Double poteau [FV]; Longueur: 151.746 cm; Surface peinturable (totale): 2885.63 cm2; Hauteur: 50 cm; Surface (Longueur x Hauteur): 7587.31 cm2
IFC_Pset_Géométrie_DÉCALAGE - initial: 0 cm; final: 0 cm; latéral: 0 cm
IFC_Pset_Système de Référence Altimétrique_INFÉRIEUR - NIVEAU: Rez-de-Jardin (Rez-de-Jardin 15545); delta: 48 cm
IFC_Pset_Matériaux - Principal: Beige; Matériau (2): Beige; Matériau (3): Beige; Matériau (4): Beige
Pset_RailingCommon - Reference: Double poteau [FV] (..\Garde-corps et parapets sur mur\); Height: 100 cm

# IfcRailing: Double poteau [FV] (2)
In: Mezzanine
Type - Material: Blanc trafic
Description: Garde-corps; Group: ...de garde-corps = Double poteau [FV]; ...de matériaux et couleurs = Blanc trafic; ...de matériaux et couleurs - 1 = Blanc trafic; ...de matériaux et couleurs - 2 = Blanc trafic; ...de matériaux et couleurs - 3 = Blanc trafic
__RECOGNIZE__ - TPLG: 141; TPLG_OD: 141; GENERATE: 1
CTLG_EXTERNAL_LINK - 0, DocType: 4; 0, Tag: 4000; 0, Crc: 481760863; 1, DocType: 2; 1, Tag: 0; 1, Crc: 1192038750; 2, DocType: 2; 2, Tag: 1; 2, Crc: 1192038750; 3, DocType: 2; 3, Tag: 2; 3, Crc: 1192038750; 4, DocType: 2; 4, Tag: 3; 4, Crc: 1192038750
IFC_PSET_PolygonOffset - polygonOffsetFactor: 2; polygonOffsetUnits: 2
IFC_Pset_Caractéristiques - Numéro niveau: 06; Titre niveau: Mezzanine
IFC_Pset_Géométrie - Modèle: Double poteau [FV]; Hauteur: 50 cm
IFC_Pset_Géométrie_DÉCALAGE - initial: 0 cm; final: 0 cm; latéral: 0 cm
IFC_Pset_Système de Référence Altimétrique_INFÉRIEUR - NIVEAU: Mezzanine (Mezzanine 49003)
IFC_Pset_Matériaux - Principal: Blanc trafic; Matériau (2): Blanc trafic; Matériau (3): Blanc trafic; Matériau (4): Blanc trafic
Pset_RailingCommon - Reference: Double poteau [FV] (..\Garde-corps et parapets sur mur\); Height: 100 cm
Name | __RECOGNIZE__, ID = IFC_Pset_Caractéristiques, ID | Numérotation | Longueur (cm) | Surface peinturable (totale) (cm2) | Surface (Longueur x Hauteur) (cm2) | delta (cm)
Garde-corps 1519647 | 1519647 | 32 | 127.481 | 1952.69 | 6374.04 | -25
Garde-corps 1519654 | 1519654 | 33 | 154.004 | 2285.57 | 7700.19 | -182

# IfcRailing: Double poteau [FV] (2)
In: Mezzanine
Type - Material: Jaune 255-255-0
Description: Garde-corps; Group: ...de garde-corps = Double poteau [FV]; ...de matériaux et couleurs = Jaune 255-255-0; ...de matériaux et couleurs - 1 = Jaune 255-255-0; ...de matériaux et couleurs - 2 = Jaune 255-255-0; ...de matériaux et couleurs - 3 = Jaune 255-255-0
__RECOGNIZE__ - TPLG: 141; TPLG_OD: 141; GENERATE: 1
CTLG_EXTERNAL_LINK - 0, DocType: 4; 0, Tag: 4000; 0, Crc: 481760863; 1, DocType: 2; 1, Tag: 0; 1, Crc: -799740758; 2, DocType: 2; 2, Tag: 1; 2, Crc: -799740758; 3, DocType: 2; 3, Tag: 2; 3, Crc: -799740758; 4, DocType: 2; 4, Tag: 3; 4, Crc: -799740758
IFC_PSET_PolygonOffset - polygonOffsetFactor: 2; polygonOffsetUnits: 2
IFC_Pset_Caractéristiques - Numéro niveau: 06; Titre niveau: Mezzanine
IFC_Pset_Géométrie - Modèle: Double poteau [FV]; Hauteur: 50 cm
IFC_Pset_Géométrie_DÉCALAGE - initial: 0 cm; final: 0 cm; latéral: 0 cm
IFC_Pset_Système de Référence Altimétrique_INFÉRIEUR - NIVEAU: Mezzanine (Mezzanine 49003)
IFC_Pset_Matériaux - Principal: Jaune 255-255-0; Matériau (2): Jaune 255-255-0; Matériau (3): Jaune 255-255-0; Matériau (4): Jaune 255-255-0
Pset_RailingCommon - Reference: Double poteau [FV] (..\Garde-corps et parapets sur mur\); Height: 100 cm
Name | __RECOGNIZE__, ID = IFC_Pset_Caractéristiques, ID | Numérotation | Longueur (cm) | Surface peinturable (totale) (cm2) | Surface (Longueur x Hauteur) (cm2) | delta (cm)
Garde-corps 192719 | 192719 | 13 | 946.217 | 12228 | 47310.8 | 45
Garde-corps 192718 | 192718 | 12 | 946.564 | 12232.3 | 47328.2 | 50

# IfcRailing: Double poteau [FV] (4)
In: Rez-de-Jardin
Type - Material: Jaune 255-255-0, Aluminium satiné
Description: Garde-corps; Group: ...de matériaux et couleurs = Aluminium satiné; ...de garde-corps = Double poteau [FV]; ...de matériaux et couleurs - 1 = Jaune 255-255-0; ...de matériaux et couleurs - 2 = Jaune 255-255-0; ...de matériaux et couleurs - 3 = Jaune 255-255-0
__RECOGNIZE__ - TPLG: 141; TPLG_OD: 141; GENERATE: 1
CTLG_EXTERNAL_LINK - 0, DocType: 4; 0, Tag: 4000; 0, Crc: 481760863; 1, DocType: 2; 1, Tag: 0; 1, Crc: 1305662025; 2, DocType: 2; 2, Tag: 1; 2, Crc: -799740758; 3, DocType: 2; 3, Tag: 2; 3, Crc: -799740758; 4, DocType: 2; 4, Tag: 3; 4, Crc: -799740758
IFC_PSET_PolygonOffset - polygonOffsetFactor: 2; polygonOffsetUnits: 2
IFC_Pset_Caractéristiques - Numéro niveau: 02; Titre niveau: Rez-de-Jardin
IFC_Pset_Géométrie - Modèle: Double poteau [FV]; Hauteur: 50 cm
IFC_Pset_Géométrie_DÉCALAGE - initial: 0 cm; final: 0 cm; latéral: 0 cm
IFC_Pset_Système de Référence Altimétrique_INFÉRIEUR - NIVEAU: Rez-de-Jardin (Rez-de-Jardin 15545)
IFC_Pset_Matériaux - Principal: Aluminium satiné; Matériau (2): Jaune 255-255-0; Matériau (3): Jaune 255-255-0; Matériau (4): Jaune 255-255-0
Pset_RailingCommon - Reference: Double poteau [FV] (..\Garde-corps et parapets sur mur\); Height: 100 cm
Name | __RECOGNIZE__, ID = IFC_Pset_Caractéristiques, ID | Numérotation | Longueur (cm) | Surface peinturable (totale) (cm2) | Surface (Longueur x Hauteur) (cm2) | delta (cm)
Garde-corps 294725 | 294725 | 24 | 180.03 | 2740.61 | 9001.5 | 15
Garde-corps 294724 | 294724 | 23 | 175.801 | 2690.03 | 8790.07 | 15
Garde-corps 294701 | 294701 | 22 | 597.464 | 8790.96 | 29873.2 | 150
Garde-corps 292678 | 292678 | 21 | 2193.14 | 31155.6 | 109657 | 150

# IfcRailing: Façonné [F] (6)
Type - Material: Aluminium satiné, Aluminium mat
Description: Garde-corps; Group: ...de garde-corps = Façonné [F]; ...de matériaux et couleurs = Aluminium satiné; ...de matériaux et couleurs - 1 = Aluminium mat; ...de matériaux et couleurs - 2 = Aluminium mat; ...de matériaux et couleurs - 3 = Aluminium mat
__RECOGNIZE__ - TPLG: 141; TPLG_OD: 141; GENERATE: 1
CTLG_EXTERNAL_LINK - 0, DocType: 4; 0, Tag: 4000; 0, Crc: 2062257881; 1, DocType: 2; 1, Tag: 0; 1, Crc: -212966465; 2, DocType: 2; 2, Tag: 1; 2, Crc: 913068333; 3, DocType: 2; 3, Tag: 2; 3, Crc: 913068333; 4, DocType: 2; 4, Tag: 3; 4, Crc: 913068333
IFC_PSET_PolygonOffset - polygonOffsetFactor: 2; polygonOffsetUnits: 2
IFC_Pset_Géométrie - Modèle: Façonné [F]; Hauteur: 100 cm
IFC_Pset_Géométrie_DÉCALAGE - initial: 0 cm; final: 0 cm; latéral: 0 cm
IFC_Pset_Matériaux - Principal: Aluminium satiné; Matériau (2): Aluminium mat; Matériau (3): Aluminium mat; Matériau (4): Aluminium mat
Pset_RailingCommon - Reference: Façonné [F] (..\Main courante\); Height: 100 cm
Name | In | __RECOGNIZE__, ID = IFC_Pset_Caractéristiques, ID | Numérotation | Numéro niveau | Titre niveau | Longueur (cm) | Surface peinturable (totale) (cm2) | Surface (Longueur x Hauteur) (cm2) | NIVEAU | delta (cm)
Garde-corps 1669877 | Rez-de-Jardin | 1669877 | 35 | 02 | Rez-de-Jardin | 194.152 | 4313.25 | 19415.2 | Rez-de-Jardin (Rez-de-Jardin 15545) | -105
Garde-corps 1669875 | Rez-de-Jardin | 1669875 | 34 | 02 | Rez-de-Jardin | 179.944 | 3396.71 | 17994.4 | Rez-de-Jardin (Rez-de-Jardin 15545) | 0
Garde-corps 1669881 | Rez-de-chaussée | 1669881 | 39 | 03 | Rez-de-chaussée | 187.969 | 3591.66 | 18796.9 | Rez-de-chaussée (Rez-de-chaussée 1047) | 358
Garde-corps 1669878 | Rez-de-chaussée | 1669878 | 36 | 03 | Rez-de-chaussée | 188.285 | 3573.48 | 18828.5 | Rez-de-chaussée (Rez-de-chaussée 1047) | 5
Garde-corps 1701999 | Niveau 1 | 1701999 | 40 | 04 | Niveau 1 | 176.83 | 3371.73 | 17683 | Niveau 1 (Niveau 1 2343) | 3
Garde-corps 1702002 | Niveau 1 | 1702002 | 42 | 04 | Niveau 1 | 196.724 | 3726.84 | 19672.4 | Niveau 1 (Niveau 1 2343) | 377

# IfcRailing: Façonné [F], Garde-corps 13544
In: Rez-de-chaussée
Type - Material: Fer, Aluminium mat
Description: Garde-corps; Group: ...de garde-corps = Façonné [F]; ...de matériaux et couleurs - 1 = Aluminium mat; ...de matériaux et couleurs - 2 = Aluminium mat; ...de matériaux et couleurs - 3 = Aluminium mat; ...de matériaux et couleurs = Fer
__RECOGNIZE__ - ID: 13544; TPLG: 141; TPLG_OD: 141; GENERATE: 1
CTLG_EXTERNAL_LINK - 0, DocType: 4; 0, Tag: 4000; 0, Crc: 2062257881; 1, DocType: 2; 1, Tag: 0; 1, Crc: 528919847; 2, DocType: 2; 2, Tag: 1; 2, Crc: 913068333; 3, DocType: 2; 3, Tag: 2; 3, Crc: 913068333; 4, DocType: 2; 4, Tag: 3; 4, Crc: 913068333
IFC_PSET_PolygonOffset - polygonOffsetFactor: 2; polygonOffsetUnits: 2
IFC_Pset_Caractéristiques - ID: 13544; Numérotation: 01; Numéro niveau: 03; Titre niveau: Rez-de-chaussée
IFC_Pset_Géométrie - Modèle: Façonné [F]; Longueur: 165.618 cm; Surface peinturable (totale): 3176.6 cm2; Hauteur: 100 cm; Surface (Longueur x Hauteur): 16561.8 cm2
IFC_Pset_Géométrie_DÉCALAGE - initial: 0 cm; final: 0 cm; latéral: 0 cm
IFC_Pset_Système de Référence Altimétrique_INFÉRIEUR - NIVEAU: Rez-de-chaussée (Rez-de-chaussée 1047); delta: -15 cm
IFC_Pset_Matériaux - Principal: Fer; Matériau (2): Aluminium mat; Matériau (3): Aluminium mat; Matériau (4): Aluminium mat
Pset_RailingCommon - Reference: Façonné [F] (..\Main courante\); Height: 100 cm

# IfcRailing: Traverses en bois avec panneau à maille carrée (2)
In: Rez-de-Jardin
Type - Material: Aluminium mat, Vert signal
Description: Garde-corps; Group: ...de matériaux et couleurs - 1 = Aluminium mat; ...de matériaux et couleurs - 2 = Aluminium mat; ...de matériaux et couleurs - 3 = Aluminium mat; ...de garde-corps = Traverses en bois avec panneau à maille carrée; ...de matériaux et couleurs = Vert signal
__RECOGNIZE__ - TPLG: 141; TPLG_OD: 141; GENERATE: 1
CTLG_EXTERNAL_LINK - 0, DocType: 4; 0, Tag: 4000; 0, Crc: -1266848377; 1, DocType: 2; 1, Tag: 0; 1, Crc: -151031501; 2, DocType: 2; 2, Tag: 1; 2, Crc: 913068333; 3, DocType: 2; 3, Tag: 2; 3, Crc: 913068333; 4, DocType: 2; 4, Tag: 3; 4, Crc: 913068333
IFC_PSET_PolygonOffset - polygonOffsetFactor: 2; polygonOffsetUnits: 2
IFC_Pset_Caractéristiques - Numéro niveau: 02; Titre niveau: Rez-de-Jardin
IFC_Pset_Géométrie - Modèle: Traverses en bois avec panneau à maille carrée; Hauteur: 203 cm
IFC_Pset_Géométrie_DÉCALAGE - initial: 0 cm; final: 0 cm; latéral: 0 cm
IFC_Pset_Système de Référence Altimétrique_INFÉRIEUR - NIVEAU: Rez-de-Jardin (Rez-de-Jardin 15545); delta: 115 cm
IFC_Pset_Matériaux - Principal: Vert signal; Matériau (2): Aluminium mat; Matériau (3): Aluminium mat; Matériau (4): Aluminium mat
Pset_RailingCommon - Reference: Traverses en bois avec panneau à maille carrée (..\Clôtures\); Height: 100 cm
Name | __RECOGNIZE__, ID = IFC_Pset_Caractéristiques, ID | Numérotation | Longueur (cm) | Surface peinturable (totale) (cm2) | Surface (Longueur x Hauteur) (cm2)
Garde-corps 1824271 | 1824271 | 58 | 115.743 | 26407.9 | 23495.8
Garde-corps 1824234 | 1824234 | 57 | 1863.48 | 383146 | 378285

# IfcRailing: Tube rond [FV] (21)
Type - Material: Aluminium satiné, Aluminium mat
Description: Garde-corps; Group: ...de matériaux et couleurs = Aluminium satiné; ...de matériaux et couleurs - 1 = Aluminium mat; ...de matériaux et couleurs - 2 = Aluminium mat; ...de matériaux et couleurs - 3 = Aluminium mat; ...de garde-corps = Tube rond [FV]
__RECOGNIZE__ - TPLG: 141; TPLG_OD: 141; GENERATE: 1
CTLG_EXTERNAL_LINK - 0, DocType: 4; 0, Tag: 4000; 0, Crc: 1524146922; 1, DocType: 2; 1, Tag: 0; 1, Crc: -212966465; 2, DocType: 2; 2, Tag: 1; 2, Crc: 913068333; 3, DocType: 2; 3, Tag: 2; 3, Crc: 913068333; 4, DocType: 2; 4, Tag: 3; 4, Crc: 913068333
IFC_PSET_PolygonOffset - polygonOffsetFactor: 2; polygonOffsetUnits: 2
IFC_Pset_Géométrie - Modèle: Tube rond [FV]; Hauteur: 94.7 cm
IFC_Pset_Géométrie_DÉCALAGE - initial: 0 cm; final: 0 cm; latéral: 0 cm
IFC_Pset_Matériaux - Principal: Aluminium satiné; Matériau (2): Aluminium mat; Matériau (3): Aluminium mat; Matériau (4): Aluminium mat
Pset_RailingCommon - Reference: Tube rond [FV] (..\Garde-corps et parapets sur mur\); Height: 100 cm
Name | In | __RECOGNIZE__, ID = IFC_Pset_Caractéristiques, ID | Numérotation | Numéro niveau | Titre niveau | Longueur (cm) | Surface peinturable (totale) (cm2) | Surface (Longueur x Hauteur) (cm2) | NIVEAU | delta (cm)
Garde-corps 1702008 | Rez-de-Jardin | 1702008 | 47 | 02 | Rez-de-Jardin | 503.4 | 22748.5 | 47672 | Rez-de-Jardin (Rez-de-Jardin 15545) | 115
Garde-corps 149751 | Rez-de-Jardin | 149751 | 10 | 02 | Rez-de-Jardin | 180.364 | 8001.97 | 17080.4 | Rez-de-Jardin (Rez-de-Jardin 15545) | 68
Garde-corps 149700 | Rez-de-Jardin | 149700 | 09 | 02 | Rez-de-Jardin | 181.697 | 8039.96 | 17206.7 | Rez-de-Jardin (Rez-de-Jardin 15545) | 68
Garde-corps 92065 | Rez-de-Jardin | 92065 | 03 | 02 | Rez-de-Jardin | 318.982 | 16469.1 | 30207.6 | Rez-de-Jardin (Rez-de-Jardin 15545) | 130
Garde-corps 92066 | Rez-de-Jardin | 92066 | 04 | 02 | Rez-de-Jardin | 320.6 | 16515.8 | 30360.8 | Rez-de-Jardin (Rez-de-Jardin 15545) | 130
Garde-corps 1669880 | Rez-de-chaussée | 1669880 | 38 | 03 | Rez-de-chaussée | 511.17 | 25429.1 | 48407.8 | Rez-de-chaussée (Rez-de-chaussée 1047) | 0
Garde-corps 1669879 | Rez-de-chaussée | 1669879 | 37 | 03 | Rez-de-chaussée | 398.915 | 18430.7 | 37777.2 | Rez-de-chaussée (Rez-de-chaussée 1047) | 116
Garde-corps 1702003 | Rez-de-chaussée | 1702003 | 43 | 03 | Rez-de-chaussée | 145.339 | 6799.95 | 13763.6 | Rez-de-chaussée (Rez-de-chaussée 1047) | 238
Garde-corps 1702004 | Rez-de-chaussée | 1702004 | 44 | 03 | Rez-de-chaussée | 147.142 | 6852.05 | 13934.3 | Rez-de-chaussée (Rez-de-chaussée 1047) | 238
Garde-corps 1702031 | Rez-de-chaussée | 1702031 | 55 | 03 | Rez-de-chaussée | 159.227 | 7202.49 | 15078.8 | Rez-de-chaussée (Rez-de-chaussée 1047) | 5
Garde-corps 1702032 | Rez-de-chaussée | 1702032 | 56 | 03 | Rez-de-chaussée | 156.203 | 7115.21 | 14792.4 | Rez-de-chaussée (Rez-de-chaussée 1047) | 5
Garde-corps 1702005 | Rez-de-chaussée | 1702005 | 45 | 03 | Rez-de-chaussée | 507.89 | 23116.1 | 48097.2 | Rez-de-chaussée (Rez-de-chaussée 1047) | 240
Garde-corps 1702012 | Rez-de-chaussée | 1702012 | 48 | 03 | Rez-de-chaussée | 171.118 | 7545.73 | 16204.9 | Rez-de-chaussée (Rez-de-chaussée 1047) | 0
Garde-corps 1702000 | Niveau 1 | 1702000 | 41 | 04 | Niveau 1 | 391.279 | 19653.1 | 37054.1 | Niveau 1 (Niveau 1 2343) | 114
Garde-corps 1702028 | Niveau 1 | 1702028 | 54 | 04 | Niveau 1 | 155.892 | 7106.22 | 14763 | Niveau 1 (Niveau 1 2343) | 5
Garde-corps 1702027 | Niveau 1 | 1702027 | 53 | 04 | Niveau 1 | 162.578 | 7299.21 | 15396.2 | Niveau 1 (Niveau 1 2343) | 5
Garde-corps 1702006 | Niveau 1 | 1702006 | 46 | 04 | Niveau 1 | 179.94 | 7800.37 | 17040.3 | Niveau 1 (Niveau 1 2343) | 3
Garde-corps 1702015 | Niveau 1 | 1702015 | 49 | 04 | Niveau 1 | 1342.2 | 62002.7 | 127107 | Niveau 1 (Niveau 1 2343) | 5
Garde-corps 1702024 | Niveau 2 | 1702024 | 52 | 05 | Niveau 2 | 156.922 | 7135.96 | 14860.5 | Niveau 2 (Niveau 2 13545) | 5
Garde-corps 1702023 | Niveau 2 | 1702023 | 51 | 05 | Niveau 2 | 158.05 | 7168.53 | 14967.4 | Niveau 2 (Niveau 2 13545) | 5
Garde-corps 1702016 | Niveau 2 | 1702016 | 50 | 05 | Niveau 2 | 178.588 | 7761.38 | 16912.3 | Niveau 2 (Niveau 2 13545) | 6

# IfcRailing: Tube rond [FV], Garde-corps 574860
In: Rez-de-Jardin
Type - Material: Blanc trafic, Aluminium satiné
Description: Garde-corps; Group: ...de matériaux et couleurs = Aluminium satiné; ...de garde-corps = Tube rond [FV]; ...de matériaux et couleurs - 1 = Blanc trafic; ...de matériaux et couleurs - 2 = Blanc trafic; ...de matériaux et couleurs - 3 = Blanc trafic
__RECOGNIZE__ - ID: 574860; TPLG: 141; TPLG_OD: 141; GENERATE: 1
CTLG_EXTERNAL_LINK - 0, DocType: 4; 0, Tag: 4000; 0, Crc: 1524146922; 1, DocType: 2; 1, Tag: 0; 1, Crc: -212966465; 2, DocType: 2; 2, Tag: 1; 2, Crc: -848491367; 3, DocType: 2; 3, Tag: 2; 3, Crc: -848491367; 4, DocType: 2; 4, Tag: 3; 4, Crc: -848491367
IFC_PSET_PolygonOffset - polygonOffsetFactor: 2; polygonOffsetUnits: 2
IFC_Pset_Caractéristiques - ID: 574860; Numérotation: 31; Numéro niveau: 02; Titre niveau: Rez-de-Jardin
IFC_Pset_Géométrie - Modèle: Tube rond [FV]; Longueur: 340.427 cm; Surface peinturable (totale): 15429.9 cm2; Hauteur: 94.7 cm; Surface (Longueur x Hauteur): 32238.5 cm2
IFC_Pset_Géométrie_DÉCALAGE - initial: 0 cm; final: 0 cm; latéral: 0 cm
IFC_Pset_Système de Référence Altimétrique_INFÉRIEUR - NIVEAU: Rez-de-Jardin (Rez-de-Jardin 15545); delta: 0 cm
IFC_Pset_Matériaux - Principal: Aluminium satiné; Matériau (2): Blanc trafic; Matériau (3): Blanc trafic; Matériau (4): Blanc trafic
Pset_RailingCommon - Reference: Tube rond [FV] (..\Garde-corps et parapets sur mur\); Height: 100 cm

# IfcRoof (13)
__RECOGNIZE__ - TPLG: 880; TPLG_OD: 880; GENERATE: 1
CTLG_EXTERNAL_LINK - 0, DocType: 2; 0, Tag: 0; 1, DocType: 2; 1, Tag: 10; 2, DocType: 2; 2, Tag: 11; 3, DocType: 9; 3, Tag: 0
IFC_PSET_PolygonOffset - polygonOffsetFactor: 2; polygonOffsetUnits: 2
IFC_Pset_Système de Référence Altimétrique_INFÉRIEUR - sous Niveau: <aucun>
IFC_Pset_Données Métré - Surface supérieur des Corniches: 0 cm2; Surface inf. et lat. des Corniches: 0 cm2; Volume des Corniches: 0 cm3
Name | In | Description = Nom sous-Niveau | __RECOGNIZE__, ID = IFC_Pset_Caractéristiques, ID | 0, Crc | 1, Crc = 2, Crc | 3, Crc | Numérotation | Numéro niveau | Titre niveau | Stratigraphie | Épaisseur (cm) | NIVEAU | delta (cm) | Périmètre (effectif) (cm) | Surface des Pans (cm2) | Surface nette du Pan (cm2) | Volume de la Couverture (cm3) | Face supérieure | Face inférieure = Face latérale | Reference | ProjectedArea (cm2) | TotalArea (cm2) = TotalSurfaceArea (cm2) | Group
Toit 954628 | Niveau 2 | Toit954628 | 954628 | -72692602 | -746779066 | -1895805156 | 09 | 05 | Niveau 2 | default [50,00] | 5 | Niveau 2 (Niveau 2 13545) | 52 | 2180 | 171700 | 171700 | 860000 | Acier inoxydable opaque | Blanc | default [50,00] (..\HORIZONTALES\Default\) | 17.0117 | 17.1714 | ...de matériaux et couleurs - 1 = Blanc; ...de matériaux et couleurs - 2 = Blanc; ...de stratigraphies = default; ...de matériaux et couleurs = Acier inoxydable opaque
Toit 975128 | Mezzanine | Toit975128 | 975128 | -1568333279 | -1568333279 | 1431898655 | 12 | 06 | Mezzanine | default [70,00] | 7 | Mezzanine (Mezzanine 49003) | 102 | 271 | 5500 | 5500 | 40000 | Pierre de sarnico | Pierre de sarnico | default [70,00] (..\HORIZONTALES\Default\) | 0.373686 | 0.551937 | ...de stratigraphies = default; ...de matériaux et couleurs = Pierre de sarnico; ...de matériaux et couleurs - 1 = Pierre de sarnico; ...de matériaux et couleurs - 2 = Pierre de sarnico
Toit 975127 | Mezzanine | Toit975127 | 975127 | -1568333279 | -1568333279 | 1431898655 | 11 | 06 | Mezzanine | default [70,00] | 7 | Mezzanine (Mezzanine 49003) | 100 | 271 | 5500 | 5500 | 40000 | Pierre de sarnico | Pierre de sarnico | default [70,00] (..\HORIZONTALES\Default\) | 0.373686 | 0.551937 | ...de stratigraphies = default; ...de matériaux et couleurs = Pierre de sarnico; ...de matériaux et couleurs - 1 = Pierre de sarnico; ...de matériaux et couleurs - 2 = Pierre de sarnico
Toit 959282 | Couverture | Toit959282 | 959282 | -72692602 | -746779066 | -1895805156 | 10 | 07 | Couverture | default [50,00] | 5 | Couverture (Couverture 2134) | -350 | 1657 | 103600 | 103600 | 520000 | Acier inoxydable opaque | Blanc | default [50,00] (..\HORIZONTALES\Default\) | 10.1701 | 10.3608 | ...de matériaux et couleurs - 1 = Blanc; ...de matériaux et couleurs - 2 = Blanc; ...de stratigraphies = default; ...de matériaux et couleurs = Acier inoxydable opaque
Toit 943674 | Couverture | Toit943674 | 943674 | 1792517069 | -746779066 | -1895805156 | 08 | 07 | Couverture | default [50,00] | 5 | Couverture (Couverture 2134) | -7 | 2615 | 250600 | 250600 | 1250000 | Acier inoxydable brossé | Blanc | default [50,00] (..\HORIZONTALES\Default\) | 23.6865 | 25.0611 | ...de matériaux et couleurs - 1 = Blanc; ...de matériaux et couleurs - 2 = Blanc; ...de stratigraphies = default; ...de matériaux et couleurs = Acier inoxydable brossé
Toit 1510486 | Couverture | Toit1510486 | 1510486 | -72692602 | -746779066 | -1895805156 | 13 | 07 | Couverture | default [50,00] | 5 | Couverture (Couverture 2134) | -241.5 | 637 | 16000 | 16000 | 80000 | Acier inoxydable opaque | Blanc | default [50,00] (..\HORIZONTALES\Default\) | 1.57484 | 1.60004 | ...de matériaux et couleurs - 1 = Blanc; ...de matériaux et couleurs - 2 = Blanc; ...de stratigraphies = default; ...de matériaux et couleurs = Acier inoxydable opaque
Toit 795368 | Couverture | Toit795368 | 795368 | -72692602 | -746779066 | -1895805156 | 07 | 07 | Couverture | default [50,00] | 5 | Couverture (Couverture 2134) | -36 | 4054 | 610500 | 606400 | 3050000 | Acier inoxydable opaque | Blanc | default [50,00] (..\HORIZONTALES\Default\) | 56.2603 | 61.0473 | ...de matériaux et couleurs - 1 = Blanc; ...de matériaux et couleurs - 2 = Blanc; ...de stratigraphies = default; ...de matériaux et couleurs = Acier inoxydable opaque
Toit 793923 | Couverture | Toit793923 | 793923 | -1590192294 | -1590192294 | -1895805156 | 03 | 07 | Couverture | default [50,00] | 5 | Couverture (Couverture 2134) | -260 | 3669 | 1095100 | 1083600 | 6400000 | Ardoise gris 60x30 décalé | Ardoise gris 60x30 décalé | default [50,00] (..\HORIZONTALES\Default\) | 67.0624 | 109.514 | ...de stratigraphies = default; ...de matériaux et couleurs = Ardoise gris 60x30 décalé; ...de matériaux et couleurs - 1 = Ardoise gris 60x30 décalé; ...de matériaux et couleurs - 2 = Ardoise gris 60x30 décalé
Toit 783918 | Couverture | Toit783918 | 783918 | -1590192294 | -1590192294 | -1895805156 | 02 | 07 | Couverture | default [50,00] | 5 | Couverture (Couverture 2134) | -275 | 2622 | 591500 | 591500 | 2960000 | Ardoise gris 60x30 décalé | Ardoise gris 60x30 décalé | default [50,00] (..\HORIZONTALES\Default\) | 30.4139 | 59.1513 | ...de stratigraphies = default; ...de matériaux et couleurs = Ardoise gris 60x30 décalé; ...de matériaux et couleurs - 1 = Ardoise gris 60x30 décalé; ...de matériaux et couleurs - 2 = Ardoise gris 60x30 décalé
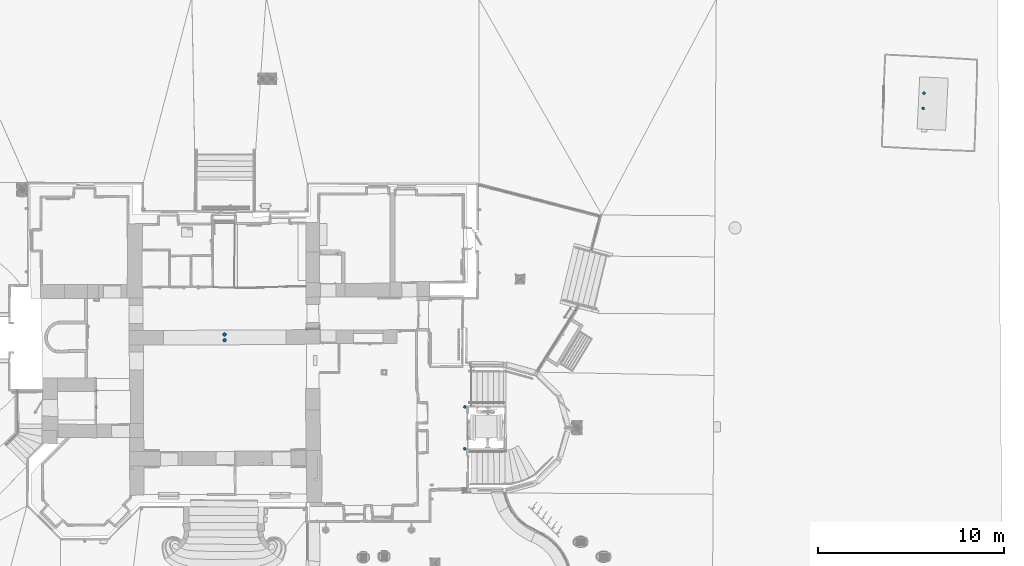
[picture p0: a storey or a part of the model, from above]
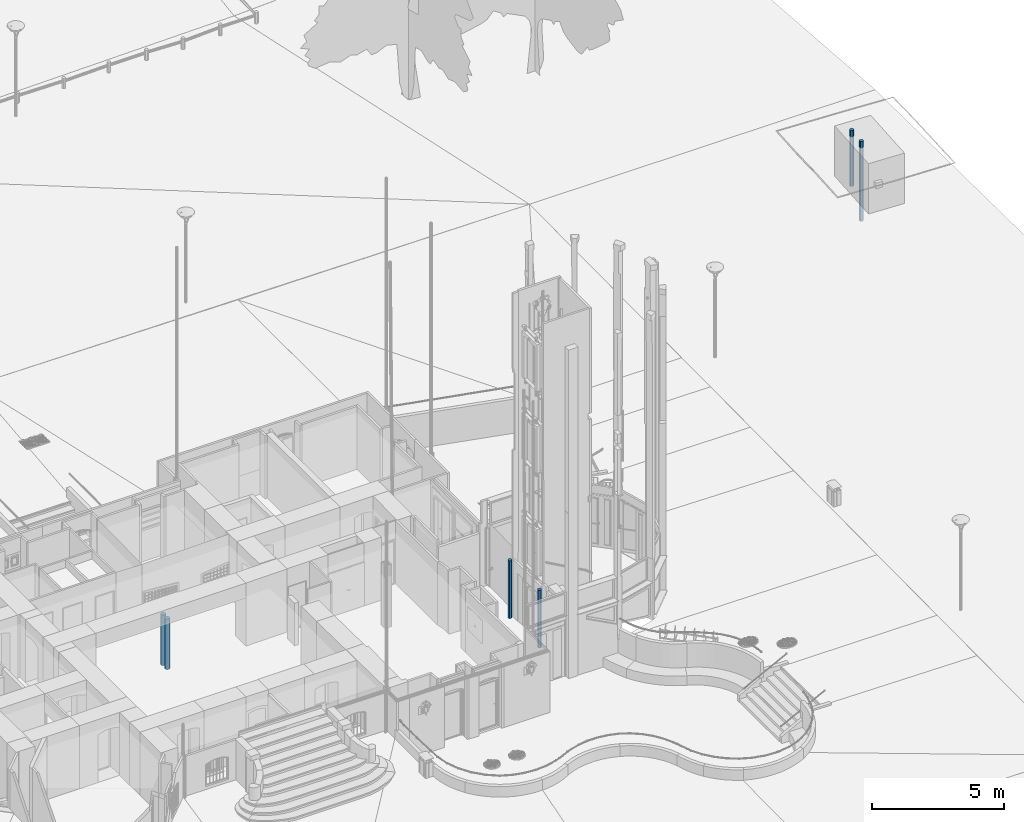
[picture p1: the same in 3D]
Properties of the parts of a building model (IFC2X3), part 17 of 37

# IfcRoof (13)
Name | In | Description = Nom sous-Niveau | __RECOGNIZE__, ID = IFC_Pset_Caractéristiques, ID | 0, Crc | 1, Crc = 2, Crc | 3, Crc | Numérotation | Numéro niveau | Titre niveau | Stratigraphie | Épaisseur (cm) | NIVEAU | delta (cm) | Périmètre (effectif) (cm) | Surface des Pans (cm2) | Surface nette du Pan (cm2) | Volume de la Couverture (cm3) | Face supérieure | Face inférieure = Face latérale | Reference | ProjectedArea (cm2) | TotalArea (cm2) = TotalSurfaceArea (cm2) | Group
Toit 782750 | Couverture | Toit782750 | 782750 | -1590192294 | -1590192294 | -1895805156 | 01 | 07 | Couverture | default [50,00] | 5 | Couverture (Couverture 2134) | -250 | 2525 | 632600 | 632600 | 3160000 | Ardoise gris 60x30 décalé | Ardoise gris 60x30 décalé | default [50,00] (..\HORIZONTALES\Default\) | 30.8876 | 63.2625 | ...de stratigraphies = default; ...de matériaux et couleurs = Ardoise gris 60x30 décalé; ...de matériaux et couleurs - 1 = Ardoise gris 60x30 décalé; ...de matériaux et couleurs - 2 = Ardoise gris 60x30 décalé
Toit 795367 | Couverture | Toit795367 | 795367 | -1590192294 | -1590192294 | -1895805156 | 06 | 07 | Couverture | default [50,00] | 5 | Couverture (Couverture 2134) | -250 | 2971 | 482700 | 482700 | 2410000 | Ardoise gris 60x30 décalé | Ardoise gris 60x30 décalé | default [50,00] (..\HORIZONTALES\Default\) | 34.8927 | 48.2712 | ...de stratigraphies = default; ...de matériaux et couleurs = Ardoise gris 60x30 décalé; ...de matériaux et couleurs - 1 = Ardoise gris 60x30 décalé; ...de matériaux et couleurs - 2 = Ardoise gris 60x30 décalé
Toit 795362 | Couverture | Toit795362 | 795362 | -1590192294 | -1590192294 | -1895805156 | 05 | 07 | Couverture | default [50,00] | 5 | Couverture (Couverture 2134) | -260 | 5365 | 1063100 | 1025400 | 5310000 | Ardoise gris 60x30 décalé | Ardoise gris 60x30 décalé | default [50,00] (..\HORIZONTALES\Default\) | 82.0129 | 106.313 | ...de stratigraphies = default; ...de matériaux et couleurs = Ardoise gris 60x30 décalé; ...de matériaux et couleurs - 1 = Ardoise gris 60x30 décalé; ...de matériaux et couleurs - 2 = Ardoise gris 60x30 décalé
Toit 793924 | Couverture | Toit793924 | 793924 | -1590192294 | -1590192294 | -1895805156 | 04 | 07 | Couverture | default [50,00] | 5 | Couverture (Couverture 2134) | -270 | 3235 | 907100 | 893600 | 4530000 | Ardoise gris 60x30 décalé | Ardoise gris 60x30 décalé | default [50,00] (..\HORIZONTALES\Default\) | 48.7067 | 90.7073 | ...de stratigraphies = default; ...de matériaux et couleurs = Ardoise gris 60x30 décalé; ...de matériaux et couleurs - 1 = Ardoise gris 60x30 décalé; ...de matériaux et couleurs - 2 = Ardoise gris 60x30 décalé

# IfcSlab (85)
Name | In | PredefinedType | Material | ID | TPLG = TPLG_OD | GENERATE | Reference | GrossVolume (cm3) | GrossArea (cm2) | NetVolume (cm3) | NetArea (cm2) | Perimeter (cm) | NominalWidth (cm)
4294967285 | Rez-de-chaussée | LANDING | Blanc, Carreau décoré (85) | -11 | 2002 | 0 | Élément Escalier 3 | 1007274 | 194731
4294967267 | Rez-de-chaussée | LANDING | Épicéa | -29 | 2002 | 0 | Élément Escalier 2 | 34753 | 24460.5
4294967266 | Rez-de-chaussée | LANDING | Épicéa | -30 | 2002 | 0 | Élément Escalier 4 | 40573.2 | 28436.5
4294967280 | Niveau 1 | LANDING | Blanc, Carreau décoré (85) | -16 | 2002 | 0 | Élément Escalier 3 | 1853479 | 350455
4294967272 | Niveau 1 | LANDING | Épicéa | -24 | 2002 | 0 | Élément Escalier 2 | 105520 | 73068.1
4294967256 | Niveau 2 | LANDING | Blanc, Brèche oniciata | -40 | 2002 | 0 | Élément Escalier 4 | 42474.4 | 13485.1
Pan 4294966637 | Niveau 2 | ROOF | <aucun> 5 cm | -659 | 893 | 1 | default [50,00] (..\HORIZONTALES\Default\) | 428354 | 85670.8 | 428354 | 85670.8 | 2009 | 5
Pan 4294966636 | Niveau 2 | ROOF | <aucun> 5 cm | -660 | 893 | 1 | default [50,00] (..\HORIZONTALES\Default\) | 430215 | 86042.9 | 430215 | 86042.9 | 2010.34 | 5
Pan 4294966629 | Mezzanine | ROOF | <aucun> 7 cm | -667 | 893 | 1 | default [70,00] (..\HORIZONTALES\Default\) | 16090 | 2298.58 | 16090 | 2298.58 | 205.111 | 7
Pan 4294966628 | Mezzanine | ROOF | <aucun> 7 cm | -668 | 893 | 1 | default [70,00] (..\HORIZONTALES\Default\) | 16987.9 | 2426.84 | 16987.9 | 2426.84 | 209.109 | 7
Pan 4294966627 | Mezzanine | ROOF | <aucun> 7 cm | -669 | 893 | 1 | default [70,00] (..\HORIZONTALES\Default\) | 5557.66 | 793.951 | 5557.66 | 793.951 | 131.07 | 7
Pan 4294966626 | Mezzanine | ROOF | <aucun> 7 cm | -670 | 893 | 1 | default [70,00] (..\HORIZONTALES\Default\) | 16090 | 2298.58 | 16090 | 2298.58 | 205.111 | 7
Pan 4294966625 | Mezzanine | ROOF | <aucun> 7 cm | -671 | 893 | 1 | default [70,00] (..\HORIZONTALES\Default\) | 16987.9 | 2426.84 | 16987.9 | 2426.84 | 209.109 | 7
Pan 4294966624 | Mezzanine | ROOF | <aucun> 7 cm | -672 | 893 | 1 | default [70,00] (..\HORIZONTALES\Default\) | 5557.66 | 793.951 | 5557.66 | 793.951 | 131.07 | 7
Pan 4294966638 | Couverture | ROOF | <aucun> 5 cm | -658 | 893 | 1 | default [50,00] (..\HORIZONTALES\Default\) | 518038 | 103608 | 518038 | 103608 | 1657.14 | 5
Pan 4294966635 | Couverture | ROOF | <aucun> 5 cm | -661 | 893 | 1 | default [50,00] (..\HORIZONTALES\Default\) | 282959 | 56591.8 | 282959 | 56591.8 | 1218.32 | 5
Pan 4294966634 | Couverture | ROOF | <aucun> 5 cm | -662 | 893 | 1 | default [50,00] (..\HORIZONTALES\Default\) | 275295 | 55058.9 | 275295 | 55058.9 | 1228.17 | 5
Pan 4294966633 | Couverture | ROOF | <aucun> 5 cm | -663 | 893 | 1 | default [50,00] (..\HORIZONTALES\Default\) | 75972.1 | 15194.4 | 75972.1 | 15194.4 | 639.669 | 5
Pan 4294966632 | Couverture | ROOF | <aucun> 5 cm | -664 | 893 | 1 | default [50,00] (..\HORIZONTALES\Default\) | 382241 | 76448.1 | 382241 | 76448.1 | 1209.02 | 5
Pan 4294966631 | Couverture | ROOF | <aucun> 5 cm | -665 | 893 | 1 | default [50,00] (..\HORIZONTALES\Default\) | 236590 | 47318 | 236590 | 47318 | 1101.21 | 5
Pan 4294966630 | Couverture | ROOF | <aucun> 5 cm | -666 | 893 | 1 | default [50,00] (..\HORIZONTALES\Default\) | 80001.8 | 16000.4 | 80001.8 | 16000.4 | 636.803 | 5
Pan 4294966623 | Couverture | ROOF | <aucun> 5 cm | -673 | 893 | 1 | default [50,00] (..\HORIZONTALES\Default\) | 621511 | 124302 | 621511 | 124302 | 1685.27 | 5
Pan 4294966622 | Couverture | ROOF | <aucun> 5 cm | -674 | 893 | 1 | default [50,00] (..\HORIZONTALES\Default\) | 422903 | 84580.5 | 422903 | 84580.5 | 1342.35 | 5
Pan 4294966621 | Couverture | ROOF | <aucun> 5 cm | -675 | 893 | 1 | default [50,00] (..\HORIZONTALES\Default\) | 271805 | 54361.1 | 271805 | 54361.1 | 1203.41 | 5
Pan 4294966620 | Couverture | ROOF | <aucun> 5 cm | -676 | 893 | 1 | default [50,00] (..\HORIZONTALES\Default\) | 276897 | 55379.4 | 256437 | 51287.4 | 1464.38 | 5
Pan 4294966619 | Couverture | ROOF | <aucun> 5 cm | -677 | 893 | 1 | default [50,00] (..\HORIZONTALES\Default\) | 226771 | 45354.2 | 226771 | 45354.2 | 1112.27 | 5
Pan 4294966618 | Couverture | ROOF | <aucun> 5 cm | -678 | 893 | 1 | default [50,00] (..\HORIZONTALES\Default\) | 256893 | 51378.6 | 256893 | 51378.6 | 1156.81 | 5
Pan 4294966617 | Couverture | ROOF | <aucun> 5 cm | -679 | 893 | 1 | default [50,00] (..\HORIZONTALES\Default\) | 347082 | 69416.4 | 347082 | 69416.4 | 1397.32 | 5
Pan 4294966616 | Couverture | ROOF | <aucun> 5 cm | -680 | 893 | 1 | default [50,00] (..\HORIZONTALES\Default\) | 239210 | 47841.9 | 239210 | 47841.9 | 1320.89 | 5
Pan 4294966615 | Couverture | ROOF | <aucun> 5 cm | -681 | 893 | 1 | default [50,00] (..\HORIZONTALES\Default\) | 310370 | 62074.1 | 310370 | 62074.1 | 1380.04 | 5
Pan 4294966614 | Couverture | ROOF | <aucun> 5 cm | -682 | 893 | 1 | default [50,00] (..\HORIZONTALES\Default\) | 78922.2 | 15784.4 | 78922.2 | 15784.4 | 1079.94 | 5
Pan 4294966613 | Couverture | ROOF | <aucun> 5 cm | -683 | 893 | 1 | default [50,00] (..\HORIZONTALES\Default\) | 1004581 | 200916 | 1004581 | 200916 | 2287.88 | 5
Pan 4294966612 | Couverture | ROOF | <aucun> 5 cm | -684 | 893 | 1 | default [50,00] (..\HORIZONTALES\Default\) | 1580784 | 316157 | 1580784 | 316157 | 2840.21 | 5
Pan 4294966611 | Couverture | ROOF | <aucun> 5 cm | -685 | 893 | 1 | default [50,00] (..\HORIZONTALES\Default\) | 1084655 | 216931 | 642449 | 128490 | 3632.36 | 5
Pan 4294966609 | Couverture | ROOF | <aucun> 5 cm | -687 | 893 | 1 | default [50,00] (..\HORIZONTALES\Default\) | 1656876 | 331375 | 1114189 | 222838 | 4762.44 | 5
Pan 4294966607 | Couverture | ROOF | <aucun> 5 cm | -689 | 893 | 1 | default [50,00] (..\HORIZONTALES\Default\) | 537734 | 107547 | 537734 | 107547 | 2004.39 | 5
Pan 4294966606 | Couverture | ROOF | <aucun> 5 cm | -690 | 893 | 1 | default [50,00] (..\HORIZONTALES\Default\) | 538131 | 107626 | 538131 | 107626 | 2011.32 | 5
Pan 4294966605 | Couverture | ROOF | <aucun> 5 cm | -691 | 893 | 1 | default [50,00] (..\HORIZONTALES\Default\) | 828232 | 165646 | 828232 | 165646 | 2083.62 | 5
Pan 4294966604 | Couverture | ROOF | <aucun> 5 cm | -692 | 893 | 1 | default [50,00] (..\HORIZONTALES\Default\) | 540874 | 108175 | 540874 | 108175 | 1610.86 | 5
Pan 4294966603 | Couverture | ROOF | <aucun> 5 cm | -693 | 893 | 1 | default [50,00] (..\HORIZONTALES\Default\) | 216359 | 43271.9 | 216359 | 43271.9 | 1412.47 | 5
Pan 4294966602 | Couverture | ROOF | <aucun> 5 cm | -694 | 893 | 1 | default [50,00] (..\HORIZONTALES\Default\) | 863310 | 172662 | 863310 | 172662 | 2076.54 | 5
Pan 4294966601 | Couverture | ROOF | <aucun> 5 cm | -695 | 893 | 1 | default [50,00] (..\HORIZONTALES\Default\) | 46607.2 | 9321.44 | 46607.2 | 9321.44 | 1357.09 | 5
Pan 4294966600 | Couverture | ROOF | <aucun> 5 cm | -696 | 893 | 1 | default [50,00] (..\HORIZONTALES\Default\) | 46744.2 | 9348.85 | 46744.2 | 9348.85 | 1366.24 | 5
Pan 4294966599 | Couverture | ROOF | <aucun> 5 cm | -697 | 893 | 1 | default [50,00] (..\HORIZONTALES\Default\) | 415439 | 83087.9 | 415439 | 83087.9 | 1421.09 | 5
Pan 4294966598 | Couverture | ROOF | <aucun> 5 cm | -698 | 893 | 1 | default [50,00] (..\HORIZONTALES\Default\) | 391663 | 78332.6 | 391663 | 78332.6 | 1494.11 | 5
Pan 4294966597 | Couverture | ROOF | <aucun> 5 cm | -699 | 893 | 1 | default [50,00] (..\HORIZONTALES\Default\) | 328572 | 65714.5 | 328572 | 65714.5 | 1640 | 5
Pan 4294966596 | Couverture | ROOF | <aucun> 5 cm | -700 | 893 | 1 | default [50,00] (..\HORIZONTALES\Default\) | 389376 | 77875.1 | 389376 | 77875.1 | 1488.82 | 5
Pan 4294966595 | Couverture | ROOF | <aucun> 5 cm | -701 | 893 | 1 | default [50,00] (..\HORIZONTALES\Default\) | 332796 | 66559.2 | 332796 | 66559.2 | 1646.82 | 5
Pan 4294966594 | Couverture | ROOF | <aucun> 5 cm | -702 | 893 | 1 | default [50,00] (..\HORIZONTALES\Default\) | 223663 | 44732.7 | 223663 | 44732.7 | 1370.81 | 5
Pan 4294966593 | Couverture | ROOF | <aucun> 5 cm | -703 | 893 | 1 | default [50,00] (..\HORIZONTALES\Default\) | 388330 | 77665.9 | 388330 | 77665.9 | 1487.54 | 5
Pan 4294966592 | Couverture | ROOF | <aucun> 5 cm | -704 | 893 | 1 | default [50,00] (..\HORIZONTALES\Default\) | 404895 | 80978.9 | 404895 | 80978.9 | 1502.8 | 5
Pan 4294966591 | Couverture | ROOF | <aucun> 5 cm | -705 | 893 | 1 | default [50,00] (..\HORIZONTALES\Default\) | 200376 | 40075.3 | 200376 | 40075.3 | 1300.85 | 5
Pan 4294966590 | Couverture | ROOF | <aucun> 5 cm | -706 | 893 | 1 | default [50,00] (..\HORIZONTALES\Default\) | 165989 | 33197.7 | 165989 | 33197.7 | 1321.75 | 5
Pan 4294966589 | Couverture | ROOF | <aucun> 5 cm | -707 | 893 | 1 | default [50,00] (..\HORIZONTALES\Default\) | 23007.7 | 4601.55 | 23007.7 | 4601.55 | 1253.32 | 5
Pan 4294966588 | Couverture | ROOF | <aucun> 5 cm | -708 | 893 | 1 | default [50,00] (..\HORIZONTALES\Default\) | 24903.8 | 4980.77 | 24903.8 | 4980.77 | 1252.77 | 5
Pan 4294966587 | Couverture | ROOF | <aucun> 5 cm | -709 | 893 | 1 | default [50,00] (..\HORIZONTALES\Default\) | 24538.8 | 4907.75 | 24538.8 | 4907.75 | 1248.59 | 5
Pan 4294966586 | Couverture | ROOF | <aucun> 5 cm | -710 | 893 | 1 | default [50,00] (..\HORIZONTALES\Default\) | 23570.4 | 4714.07 | 23570.4 | 4714.07 | 1245.84 | 5
Pan 4294966585 | Couverture | ROOF | <aucun> 5 cm | -711 | 893 | 1 | default [50,00] (..\HORIZONTALES\Default\) | 21937.6 | 4387.51 | 21937.6 | 4387.51 | 1243.35 | 5
Pan 4294966584 | Couverture | ROOF | <aucun> 5 cm | -712 | 893 | 1 | default [50,00] (..\HORIZONTALES\Default\) | 25574.2 | 5114.84 | 25574.2 | 5114.84 | 1246.45 | 5
Pan 4294966583 | Couverture | ROOF | <aucun> 5 cm | -713 | 893 | 1 | default [50,00] (..\HORIZONTALES\Default\) | 193932 | 38786.3 | 193932 | 38786.3 | 1316.82 | 5
Pan 4294966582 | Couverture | ROOF | <aucun> 5 cm | -714 | 893 | 1 | default [50,00] (..\HORIZONTALES\Default\) | 1282779 | 256556 | 1282779 | 256556 | 2091.54 | 5
Pan 4294966581 | Couverture | ROOF | <aucun> 5 cm | -715 | 893 | 1 | default [50,00] (..\HORIZONTALES\Default\) | 674166 | 134833 | 674166 | 134833 | 1816.55 | 5
Pan 4294966580 | Couverture | ROOF | <aucun> 5 cm | -716 | 893 | 1 | default [50,00] (..\HORIZONTALES\Default\) | 114314 | 22862.9 | 114314 | 22862.9 | 1151.92 | 5
Pan 4294966579 | Couverture | ROOF | <aucun> 5 cm | -717 | 893 | 1 | default [50,00] (..\HORIZONTALES\Default\) | 342303 | 68460.6 | 342303 | 68460.6 | 1263.97 | 5
Pan 4294966578 | Couverture | ROOF | <aucun> 5 cm | -718 | 893 | 1 | default [50,00] (..\HORIZONTALES\Default\) | 1432954 | 286591 | 1432954 | 286591 | 2546.92 | 5
Pan 4294966577 | Couverture | ROOF | <aucun> 5 cm | -719 | 893 | 1 | default [50,00] (..\HORIZONTALES\Default\) | 444794 | 88958.7 | 444794 | 88958.7 | 1721.63 | 5
Pan 4294966576 | Couverture | ROOF | <aucun> 5 cm | -720 | 893 | 1 | default [50,00] (..\HORIZONTALES\Default\) | 338143 | 67628.7 | 293683 | 58736.7 | 1484.93 | 5
Pan 4294966575 | Couverture | ROOF | <aucun> 5 cm | -721 | 893 | 1 | default [50,00] (..\HORIZONTALES\Default\) | 231611 | 46322.1 | 187151 | 37430.1 | 1281.57 | 5
Pan 4294966574 | Couverture | ROOF | <aucun> 5 cm | -722 | 893 | 1 | default [50,00] (..\HORIZONTALES\Default\) | 220032 | 44006.4 | 220032 | 44006.4 | 1056.49 | 5
Pan 4294966573 | Couverture | ROOF | <aucun> 5 cm | -723 | 893 | 1 | default [50,00] (..\HORIZONTALES\Default\) | 247966 | 49593.2 | 203506 | 40701.2 | 1285.5 | 5
Pan 4294966572 | Couverture | ROOF | <aucun> 5 cm | -724 | 893 | 1 | default [50,00] (..\HORIZONTALES\Default\) | 359718 | 71943.6 | 359718 | 71943.6 | 1642.59 | 5
Pan 4294966571 | Couverture | ROOF | <aucun> 5 cm | -725 | 893 | 1 | default [50,00] (..\HORIZONTALES\Default\) | 882855 | 176571 | 882855 | 176571 | 2207.98 | 5
Pan 4294966570 | Couverture | ROOF | <aucun> 5 cm | -726 | 893 | 1 | default [50,00] (..\HORIZONTALES\Default\) | 191718 | 38343.6 | 136428 | 27285.6 | 1359.98 | 5
Pan 4294966569 | Couverture | ROOF | <aucun> 5 cm | -727 | 893 | 1 | default [50,00] (..\HORIZONTALES\Default\) | 187280 | 37456.1 | 187280 | 37456.1 | 1349.03 | 5
Pan 4294966568 | Couverture | ROOF | <aucun> 5 cm | -728 | 893 | 1 | default [50,00] (..\HORIZONTALES\Default\) | 120508 | 24101.7 | 120508 | 24101.7 | 876.158 | 5
Pan 4294966567 | Couverture | ROOF | <aucun> 5 cm | -729 | 893 | 1 | default [50,00] (..\HORIZONTALES\Default\) | 53446.4 | 10689.3 | 53446.4 | 10689.3 | 693.267 | 5
Pan 4294966566 | Couverture | ROOF | <aucun> 5 cm | -730 | 893 | 1 | default [50,00] (..\HORIZONTALES\Default\) | 397733 | 79546.6 | 397733 | 79546.6 | 1457.84 | 5
Pan 4294966565 | Couverture | ROOF | <aucun> 5 cm | -731 | 893 | 1 | default [50,00] (..\HORIZONTALES\Default\) | 206876 | 41375.1 | 206876 | 41375.1 | 1108.01 | 5
Pan 4294966564 | Couverture | ROOF | <aucun> 5 cm | -732 | 893 | 1 | default [50,00] (..\HORIZONTALES\Default\) | 448149 | 89629.8 | 448149 | 89629.8 | 1823.27 | 5
Pan 4294966563 | Couverture | ROOF | <aucun> 5 cm | -733 | 893 | 1 | default [50,00] (..\HORIZONTALES\Default\) | 1279310 | 255862 | 1279310 | 255862 | 2577.91 | 5
Pan 4294966562 | Couverture | ROOF | <aucun> 5 cm | -734 | 893 | 1 | default [50,00] (..\HORIZONTALES\Default\) | 530674 | 106135 | 530674 | 106135 | 1617.3 | 5
Pan 4294966561 | Couverture | ROOF | <aucun> 5 cm | -735 | 893 | 1 | default [50,00] (..\HORIZONTALES\Default\) | 878258 | 175652 | 878258 | 175652 | 2085.49 | 5
Pan 4294966560 | Couverture | ROOF | <aucun> 5 cm | -736 | 893 | 1 | default [50,00] (..\HORIZONTALES\Default\) | 448589 | 89717.8 | 448589 | 89717.8 | 1825.56 | 5
Pan 4294966559 | Couverture | ROOF | <aucun> 5 cm | -737 | 893 | 1 | default [50,00] (..\HORIZONTALES\Default\) | 882396 | 176479 | 815136 | 163027 | 2503.92 | 5
Pan 4294966558 | Couverture | ROOF | <aucun> 5 cm | -738 | 893 | 1 | default [50,00] (..\HORIZONTALES\Default\) | 67987.3 | 13597.5 | 67987.3 | 13597.5 | 1191.17 | 5

# IfcSlab: Dalle en béton armé 200 (56)
Type - Material: Carreaux en céramique 1.5 cm, Chape en béton léger 4 cm, Béton armé 13 cm, Enduit de chaux et plâtre 1.5 cm
__RECOGNIZE__ - TPLG: 249; TPLG_OD: 9003; GENERATE: 1
CTLG_EXTERNAL_LINK - 0, DocType: 2; 0, Tag: 0; 1, DocType: 2; 1, Tag: 1; 2, DocType: 2; 2, Tag: 2; 3, DocType: 9; 3, Tag: 0; 3, Crc: 73903632
IFC_PSET_PolygonOffset - polygonOffsetFactor: 2; polygonOffsetUnits: 2
IFC_Pset_Alignment - Alignment: 1
IFC_Pset_Caractéristiques - Stratigraphie: Dalle en béton armé [200,00]; Épaisseur: 20 cm
IFC_Pset_Caractéristiques_Courbe - Présent: no; Orthogonal Pente: no
Pset_SlabCommon - Reference: Dalle en béton armé [200,00] (..\HORIZONTALES\Dalle en béton armé\Dalle en béton armé\)
BaseQuantities - NominalWidth: 20 cm
Name | In | Description = Nom | __RECOGNIZE__, ID = IFC_Pset_Caractéristiques, ID | 0, Crc = 1, Crc = 2, Crc | Numérotation | Numéro niveau | Titre niveau | Type de définition | Pente | Cote Point 1 (cm) | Cote Point 2 (cm) | Cote Point 3 (cm) | NIVEAU | delta (cm) | sous Niveau | Périmètre (cm) | Surface (cm2) | Volume (cm3) | Face supérieure = Face inférieure = Face latérale | GrossVolume (cm3) = NetVolume (cm3) | GrossArea (cm2) = NetArea (cm2) | Perimeter (cm) | Group
Dalle 1824248 | Rez-de-Jardin | Dalle | 1824248 | 141849051 | 40 | 02 | Rez-de-Jardin | par trois points | 0.540393 | -193.4 | -184.4 | -193.4 | Rez-de-Jardin (Rez-de-Jardin 15545) | 98.0004 | <aucun> | 6705 | 2785900 | 55720000 | Herbe (05) | 55717451 | 2785873 | 6705.01 | ...de matériaux et couleurs = Herbe (05); ...de matériaux et couleurs - 1 = Herbe (05); ...de matériaux et couleurs - 2 = Herbe (05); ...de stratigraphies = Dalle en béton armé
Dalle 1824247 | Rez-de-Jardin | Dalle | 1824247 | 141849051 | 39 | 02 | Rez-de-Jardin | par trois points | 0.544636 | -193.3 | -193.4 | -184.4 | Rez-de-Jardin (Rez-de-Jardin 15545) | 98.1004 | <aucun> | 6586.5 | 1684400 | 33690000 | Herbe (05) | 33688942 | 1684447 | 6586.45 | ...de matériaux et couleurs = Herbe (05); ...de matériaux et couleurs - 1 = Herbe (05); ...de matériaux et couleurs - 2 = Herbe (05); ...de stratigraphies = Dalle en béton armé
Dalle 1824246 | Rez-de-Jardin | TN | 1824246 | 141849051 | 38 | 02 | Rez-de-Jardin | par trois points | 0.889976 | -193.3 | -184.4 | -179.4 | Rez-de-Jardin (Rez-de-Jardin 15545) | 98.1004 | <aucun> | 6891.5 | 1942600 | 38850000 | Herbe (05) | 38851849 | 1942592 | 6891.54 | ...de matériaux et couleurs = Herbe (05); ...de matériaux et couleurs - 1 = Herbe (05); ...de matériaux et couleurs - 2 = Herbe (05); ...de stratigraphies = Dalle en béton armé
Dalle 1824249 | Rez-de-Jardin | Dalle | 1824249 | 141849051 | 41 | 02 | Rez-de-Jardin | horizontal | 0 | -193.4 | -193.4 | -193.4 | Rez-de-Jardin (Rez-de-Jardin 15545) | 98.0004 | <aucun> | 6321.3 | 2482400 | 49650000 | Herbe (05) | 49647461 | 2482373 | 6321.31 | ...de matériaux et couleurs = Herbe (05); ...de matériaux et couleurs - 1 = Herbe (05); ...de matériaux et couleurs - 2 = Herbe (05); ...de stratigraphies = Dalle en béton armé
Dalle 1824252 | Rez-de-Jardin | TN | 1824252 | 141849051 | 44 | 02 | Rez-de-Jardin | horizontal | 0 | -184.9 | -184.9 | -184.9 | Rez-de-Jardin (Rez-de-Jardin 15545) | 106.5 | <aucun> | 3347.9 | 499200 | 9980000 | Herbe (05) | 9984984 | 499249 | 3347.81 | ...de matériaux et couleurs = Herbe (05); ...de matériaux et couleurs - 1 = Herbe (05); ...de matériaux et couleurs - 2 = Herbe (05); ...de stratigraphies = Dalle en béton armé
Dalle 1824251 | Rez-de-Jardin | Pavés extérieur12a | 1824251 | -746779066 | 43 | 02 | Rez-de-Jardin | par trois points | 2.10937 | -190.268 | -184.9 | -180.4 | Rez-de-Jardin (Rez-de-Jardin 15545) | 101.133 | <aucun> | 1323.3 | 46200 | 920000 | Blanc | 923105 | 46155.3 | 1323.29 | ...de matériaux et couleurs = Blanc; ...de stratigraphies = Dalle en béton armé; ...de matériaux et couleurs - 1 = Blanc; ...de matériaux et couleurs - 2 = Blanc
Dalle 1824250 | Rez-de-Jardin | Dalle | 1824250 | 141849051 | 42 | 02 | Rez-de-Jardin | par trois points | 0.0352111 | -184.4 | -183.9 | -183.9 | Rez-de-Jardin (Rez-de-Jardin 15545) | 107 | <aucun> | 11472.1 | 6471100 | 129420000 | Herbe (05) | 129421910 | 6471096 | 11472.1 | ...de matériaux et couleurs = Herbe (05); ...de matériaux et couleurs - 1 = Herbe (05); ...de matériaux et couleurs - 2 = Herbe (05); ...de stratigraphies = Dalle en béton armé
Dalle 294964 | Rez-de-Jardin | Parking | 294964 | -746779066 | 31 | 02 | Rez-de-Jardin | horizontal | 0 | -193.4 | -193.4 | -193.4 | Rez-de-Jardin (Rez-de-Jardin 15545) | 98 | <aucun> | 11598.1 | 6670400 | 133410000 | Blanc | 133407502 | 6670375 | 11598.1 | ...de matériaux et couleurs = Blanc; ...de stratigraphies = Dalle en béton armé; ...de matériaux et couleurs - 1 = Blanc; ...de matériaux et couleurs - 2 = Blanc
Dalle 1824255 | Rez-de-Jardin | Dalle | 1824255 | 141849051 | 45 | 02 | Rez-de-Jardin | par trois points | 0 | -184.9 | -184.9 | -184.9 | Rez-de-Jardin (Rez-de-Jardin 15545) | 106.5 | <aucun> | 5729 | 1325700 | 26510000 | Herbe (05) | 26514952 | 1325748 | 5728.99 | ...de matériaux et couleurs = Herbe (05); ...de matériaux et couleurs - 1 = Herbe (05); ...de matériaux et couleurs - 2 = Herbe (05); ...de stratigraphies = Dalle en béton armé
Dalle 1824266 | Rez-de-Jardin | TN | 1824266 | 141849051 | 55 | 02 | Rez-de-Jardin | par trois points | 4.11342 | -187.3 | -188.5 | -208.8 | Rez-de-Jardin (Rez-de-Jardin 15545) | 104.1 | <aucun> | 1478 | 96400 | 1930000 | Herbe (05) | 1927129 | 96356.5 | 1477.98 | ...de matériaux et couleurs = Herbe (05); ...de matériaux et couleurs - 1 = Herbe (05); ...de matériaux et couleurs - 2 = Herbe (05); ...de stratigraphies = Dalle en béton armé
Dalle 1824265 | Rez-de-Jardin | TN | 1824265 | 141849051 | 54 | 02 | Rez-de-Jardin | par trois points | 4.48731 | -192 | -187.3 | -201.3 | Rez-de-Jardin (Rez-de-Jardin 15545) | 99.4004 | <aucun> | 2471 | 237500 | 4750000 | Herbe (05) | 4749827 | 237491 | 2470.78 | ...de matériaux et couleurs = Herbe (05); ...de matériaux et couleurs - 1 = Herbe (05); ...de matériaux et couleurs - 2 = Herbe (05); ...de stratigraphies = Dalle en béton armé
Dalle 1824264 | Rez-de-Jardin | TN | 1824264 | 141849051 | 53 | 02 | Rez-de-Jardin | par trois points | 3.06515 | -187.9 | -192 | -200.4 | Rez-de-Jardin (Rez-de-Jardin 15545) | 103.5 | <aucun> | 2624.5 | 282400 | 5650000 | Herbe (05) | 5647275 | 282364 | 2624.35 | ...de matériaux et couleurs = Herbe (05); ...de matériaux et couleurs - 1 = Herbe (05); ...de matériaux et couleurs - 2 = Herbe (05); ...de stratigraphies = Dalle en béton armé
Dalle 1824267 | Rez-de-Jardin | Dalle | 1824267 | 141849051 | 56 | 02 | Rez-de-Jardin | par trois points | 0.885242 | -179.3 | -179.3 | -193.4 | Rez-de-Jardin (Rez-de-Jardin 15545) | 112.1 | <aucun> | 5009.3 | 1055700 | 21110000 | Herbe (05) | 21113274 | 1055664 | 5009.29 | ...de matériaux et couleurs = Herbe (05); ...de matériaux et couleurs - 1 = Herbe (05); ...de matériaux et couleurs - 2 = Herbe (05); ...de stratigraphies = Dalle en béton armé
Dalle 1824270 | Rez-de-Jardin | TN | 1824270 | 141849051 | 59 | 02 | Rez-de-Jardin | par trois points | 4.47683 | -208.8 | -179.3 | -193.3 | Rez-de-Jardin (Rez-de-Jardin 15545) | 82.6004 | <aucun> | 5447.2 | 692000 | 13840000 | Herbe (05) | 13839515 | 691976 | 5447.2 | ...de matériaux et couleurs = Herbe (05); ...de matériaux et couleurs - 1 = Herbe (05); ...de matériaux et couleurs - 2 = Herbe (05); ...de stratigraphies = Dalle en béton armé
Dalle 1824269 | Rez-de-Jardin | Dalle | 1824269 | 141849051 | 58 | 02 | Rez-de-Jardin | par trois points | 0.871466 | -179.3 | -193.4 | -193.3 | Rez-de-Jardin (Rez-de-Jardin 15545) | 112.1 | <aucun> | 5586.9 | 1461600 | 29230000 | Herbe (05) | 29231346 | 1461567 | 5586.92 | ...de matériaux et couleurs = Herbe (05); ...de matériaux et couleurs - 1 = Herbe (05); ...de matériaux et couleurs - 2 = Herbe (05); ...de stratigraphies = Dalle en béton armé
Dalle 1824268 | Rez-de-Jardin | Dalle | 1824268 | 141849051 | 57 | 02 | Rez-de-Jardin | par trois points | 3.73682 | -208.8 | -188.5 | -179.3 | Rez-de-Jardin (Rez-de-Jardin 15545) | 82.6004 | <aucun> | 2778 | 301200 | 6020000 | Herbe (05) | 6023495 | 301175 | 2777.96 | ...de matériaux et couleurs = Herbe (05); ...de matériaux et couleurs - 1 = Herbe (05); ...de matériaux et couleurs - 2 = Herbe (05); ...de stratigraphies = Dalle en béton armé
Dalle 1824259 | Rez-de-Jardin | Pavés extérieur7a | 1824259 | -746779066 | 48 | 02 | Rez-de-Jardin | horizontal | 0 | -184.9 | -184.9 | -184.9 | Rez-de-Jardin (Rez-de-Jardin 15545) | 106.5 | <aucun> | 2585.5 | 288800 | 5780000 | Blanc | 5775534 | 288777 | 2585.4 | ...de matériaux et couleurs = Blanc; ...de stratigraphies = Dalle en béton armé; ...de matériaux et couleurs - 1 = Blanc; ...de matériaux et couleurs - 2 = Blanc
Dalle 1824258 | Rez-de-Jardin | TN | 1824258 | 141849051 | 47 | 02 | Rez-de-Jardin | horizontal | 0 | -184.9 | -184.9 | -184.9 | Rez-de-Jardin (Rez-de-Jardin 15545) | 106.5 | <aucun> | 3575 | 638600 | 12770000 | Herbe (05) | 12772403 | 638620 | 3574.83 | ...de matériaux et couleurs = Herbe (05); ...de matériaux et couleurs - 1 = Herbe (05); ...de matériaux et couleurs - 2 = Herbe (05); ...de stratigraphies = Dalle en béton armé
Dalle 1824256 | Rez-de-Jardin | Dalle | 1824256 | 141849051 | 46 | 02 | Rez-de-Jardin | par trois points | 0 | -184.9 | -184.9 | -184.9 | Rez-de-Jardin (Rez-de-Jardin 15545) | 106.5 | <aucun> | 7797.8 | 1052100 | 21040000 | Herbe (05) | 21042869 | 1052143 | 7797.82 | ...de matériaux et couleurs = Herbe (05); ...de matériaux et couleurs - 1 = Herbe (05); ...de matériaux et couleurs - 2 = Herbe (05); ...de stratigraphies = Dalle en béton armé
Dalle 1824260 | Rez-de-Jardin | Dalle | 1824260 | 141849051 | 49 | 02 | Rez-de-Jardin | par trois points | 2.69154 | -187.3 | -186.9 | -190.268 | Rez-de-Jardin (Rez-de-Jardin 15545) | 104.1 | <aucun> | 1877.2 | 173200 | 3460000 | Herbe (05) | 3464653 | 173233 | 1877.15 | ...de matériaux et couleurs = Herbe (05); ...de matériaux et couleurs - 1 = Herbe (05); ...de matériaux et couleurs - 2 = Herbe (05); ...de stratigraphies = Dalle en béton armé
Dalle 1824263 | Rez-de-Jardin | TN | 1824263 | 141849051 | 52 | 02 | Rez-de-Jardin | par trois points | 2.7295 | -184.9 | -184.9 | -196.9 | Rez-de-Jardin (Rez-de-Jardin 15545) | 106.5 | <aucun> | 3816.4 | 332700 | 6650000 | Herbe (05) | 6654193 | 332710 | 3816.44 | ...de matériaux et couleurs = Herbe (05); ...de matériaux et couleurs - 1 = Herbe (05); ...de matériaux et couleurs - 2 = Herbe (05); ...de stratigraphies = Dalle en béton armé
Dalle 1824262 | Rez-de-Jardin | TN | 1824262 | 141849051 | 51 | 02 | Rez-de-Jardin | horizontal | 0 | -184.9 | -184.9 | -184.9 | Rez-de-Jardin (Rez-de-Jardin 15545) | 106.5 | <aucun> | 3668.9 | 545900 | 10920000 | Herbe (05) | 10918074 | 545904 | 3668.92 | ...de matériaux et couleurs = Herbe (05); ...de matériaux et couleurs - 1 = Herbe (05); ...de matériaux et couleurs - 2 = Herbe (05); ...de stratigraphies = Dalle en béton armé
Dalle 1824261 | Rez-de-Jardin | TN | 1824261 | 141849051 | 50 | 02 | Rez-de-Jardin | par trois points | 2.43683 | -190.3 | -200.4 | -184.9 | Rez-de-Jardin (Rez-de-Jardin 15545) | 101.1 | <aucun> | 3373.5 | 563200 | 11260000 | Herbe (05) | 11263491 | 563175 | 3373.54 | ...de matériaux et couleurs = Herbe (05); ...de matériaux et couleurs - 1 = Herbe (05); ...de matériaux et couleurs - 2 = Herbe (05); ...de stratigraphies = Dalle en béton armé
Dalle 294963 | Rez-de-Jardin | Pavés extérieur29 | 294963 | -746779066 | 30 | 02 | Rez-de-Jardin | par trois points | 0.882828 | -193.4 | -193.4 | -179.4 | Rez-de-Jardin (Rez-de-Jardin 15545) | 98 | <aucun> | 3975.4 | 632900 | 12660000 | Blanc | 12657571 | 632879 | 3975.41 | ...de matériaux et couleurs = Blanc; ...de stratigraphies = Dalle en béton armé; ...de matériaux et couleurs - 1 = Blanc; ...de matériaux et couleurs - 2 = Blanc
Dalle 294738 | Rez-de-Jardin | Pavés extérieur9 | 294738 | -746779066 | 10 | 02 | Rez-de-Jardin | horizontal | 0 | -184.9 | -184.9 | -184.9 | Rez-de-Jardin (Rez-de-Jardin 15545) | 106.5 | <aucun> | 3497.1 | 437500 | 8750000 | Blanc | 8750489 | 437524 | 3497.11 | ...de matériaux et couleurs = Blanc; ...de stratigraphies = Dalle en béton armé; ...de matériaux et couleurs - 1 = Blanc; ...de matériaux et couleurs - 2 = Blanc
Dalle 294737 | Rez-de-Jardin | Pavés extérieur8 | 294737 | -746779066 | 09 | 02 | Rez-de-Jardin | par trois points | 0 | -184.9 | -184.9 | -184.9 | Rez-de-Jardin (Rez-de-Jardin 15545) | 106.5 | <aucun> | 4164.2 | 678400 | 13570000 | Blanc | 13568980 | 678449 | 4164.25 | ...de matériaux et couleurs = Blanc; ...de stratigraphies = Dalle en béton armé; ...de matériaux et couleurs - 1 = Blanc; ...de matériaux et couleurs - 2 = Blanc
Dalle 294736 | Rez-de-Jardin | Pavés extérieur6 | 294736 | -746779066 | 08 | 02 | Rez-de-Jardin | horizontal | 0 | -184.9 | -184.9 | -184.9 | Rez-de-Jardin (Rez-de-Jardin 15545) | 106.5 | <aucun> | 4579.5 | 959400 | 19190000 | Blanc | 19187472 | 959374 | 4579.37 | ...de matériaux et couleurs = Blanc; ...de stratigraphies = Dalle en béton armé; ...de matériaux et couleurs - 1 = Blanc; ...de matériaux et couleurs - 2 = Blanc
Dalle 294739 | Rez-de-Jardin | Pavés extérieur10 | 294739 | -746779066 | 11 | 02 | Rez-de-Jardin | horizontal | 0 | -184.9 | -184.9 | -184.9 | Rez-de-Jardin (Rez-de-Jardin 15545) | 106.5 | <aucun> | 3606.8 | 528900 | 10580000 | Blanc | 10578909 | 528945 | 3606.76 | ...de matériaux et couleurs = Blanc; ...de stratigraphies = Dalle en béton armé; ...de matériaux et couleurs - 1 = Blanc; ...de matériaux et couleurs - 2 = Blanc
Dalle 294947 | Rez-de-Jardin | Pavés extérieur13 | 294947 | -746779066 | 14 | 02 | Rez-de-Jardin | par trois points | 1.63262 | -177.8 | -187.3 | -180.4 | Rez-de-Jardin (Rez-de-Jardin 15545) | 113.6 | <aucun> | 1758.3 | 122100 | 2440000 | Blanc | 2441483 | 122074 | 1758.04 | ...de matériaux et couleurs = Blanc; ...de stratigraphies = Dalle en béton armé; ...de matériaux et couleurs - 1 = Blanc; ...de matériaux et couleurs - 2 = Blanc
Dalle 294946 | Rez-de-Jardin | Pavés extérieur12 | 294946 | -746779066 | 13 | 02 | Rez-de-Jardin | par trois points | 1.59211 | -180.4 | -180.4 | -186.9 | Rez-de-Jardin (Rez-de-Jardin 15545) | 111 | <aucun> | 1515.4 | 105200 | 2100000 | Blanc | 2103584 | 105179 | 1515.37 | ...de matériaux et couleurs = Blanc; ...de stratigraphies = Dalle en béton armé; ...de matériaux et couleurs - 1 = Blanc; ...de matériaux et couleurs - 2 = Blanc
Dalle 294945 | Rez-de-Jardin | Pavés extérieur11 | 294945 | -746779066 | 12 | 02 | Rez-de-Jardin | par trois points | 1.49479 | -184.9 | -190.268 | -184.9 | Rez-de-Jardin (Rez-de-Jardin 15545) | 106.5 | <aucun> | 3224.9 | 270600 | 5410000 | Blanc | 5412338 | 270617 | 3224.86 | ...de matériaux et couleurs = Blanc; ...de stratigraphies = Dalle en béton armé; ...de matériaux et couleurs - 1 = Blanc; ...de matériaux et couleurs - 2 = Blanc
Dalle 294731 | Rez-de-Jardin | Pavés extérieur2 | 294731 | -746779066 | 03 | 02 | Rez-de-Jardin | horizontal | 0 | -184.9 | -184.9 | -184.9 | Rez-de-Jardin (Rez-de-Jardin 15545) | 106.5 | <aucun> | 1964.1 | 205800 | 4120000 | Blanc | 4116809 | 205840 | 1964.06 | ...de matériaux et couleurs = Blanc; ...de stratigraphies = Dalle en béton armé; ...de matériaux et couleurs - 1 = Blanc; ...de matériaux et couleurs - 2 = Blanc
Dalle 294730 | Rez-de-Jardin | Pavés extérieur | 294730 | -746779066 | 02 | 02 | Rez-de-Jardin | horizontal | 0 | -184.9 | -184.9 | -184.9 | Rez-de-Jardin (Rez-de-Jardin 15545) | 106.5 | <aucun> | 2943.6 | 421500 | 8430000 | Blanc | 8430032 | 421502 | 2943.41 | ...de matériaux et couleurs = Blanc; ...de stratigraphies = Dalle en béton armé; ...de matériaux et couleurs - 1 = Blanc; ...de matériaux et couleurs - 2 = Blanc
Dalle 134278 | Rez-de-Jardin | Dalle | 134278 | -746779066 | 01 | 02 | Rez-de-Jardin | horizontal | 0 | -291.4 | -291.4 | -291.4 | Rez-de-Jardin (Rez-de-Jardin 15545) | 50 | extérieur | 3232.9 | 467300 | 9350000 | Blanc | 9346032 | 467302 | 3232.93 | ...de matériaux et couleurs = Blanc; ...de stratigraphies = Dalle en béton armé; ...de matériaux et couleurs - 1 = Blanc; ...de matériaux et couleurs - 2 = Blanc
Dalle 294732 | Rez-de-Jardin | Pavés extérieur3 | 294732 | -746779066 | 04 | 02 | Rez-de-Jardin | horizontal | 0 | -184.9 | -184.9 | -184.9 | Rez-de-Jardin (Rez-de-Jardin 15545) | 106.5 | <aucun> | 2804.2 | 414700 | 8290000 | Blanc | 8293704 | 414685 | 2804.1 | ...de matériaux et couleurs = Blanc; ...de stratigraphies = Dalle en béton armé; ...de matériaux et couleurs - 1 = Blanc; ...de matériaux et couleurs - 2 = Blanc
Dalle 294735 | Rez-de-Jardin | Pavés extérieur7 | 294735 | -746779066 | 07 | 02 | Rez-de-Jardin | horizontal | 0 | -184.9 | -184.9 | -184.9 | Rez-de-Jardin (Rez-de-Jardin 15545) | 106.5 | <aucun> | 2755 | 304000 | 6080000 | Blanc | 6080697 | 304035 | 2754.72 | ...de matériaux et couleurs = Blanc; ...de stratigraphies = Dalle en béton armé; ...de matériaux et couleurs - 1 = Blanc; ...de matériaux et couleurs - 2 = Blanc
Dalle 294734 | Rez-de-Jardin | Pavés extérieur5 | 294734 | -746779066 | 06 | 02 | Rez-de-Jardin | horizontal | 0 | -184.9 | -184.9 | -184.9 | Rez-de-Jardin (Rez-de-Jardin 15545) | 106.5 | <aucun> | 2992.7 | 575600 | 11510000 | Blanc | 11511953 | 575598 | 2992.41 | ...de matériaux et couleurs = Blanc; ...de stratigraphies = Dalle en béton armé; ...de matériaux et couleurs - 1 = Blanc; ...de matériaux et couleurs - 2 = Blanc
Dalle 294733 | Rez-de-Jardin | Pavés extérieur4 | 294733 | -746779066 | 05 | 02 | Rez-de-Jardin | horizontal | 0 | -184.9 | -184.9 | -184.9 | Rez-de-Jardin (Rez-de-Jardin 15545) | 106.5 | <aucun> | 2996.7 | 370500 | 7410000 | Blanc | 7410283 | 370514 | 2996.57 | ...de matériaux et couleurs = Blanc; ...de stratigraphies = Dalle en béton armé; ...de matériaux et couleurs - 1 = Blanc; ...de matériaux et couleurs - 2 = Blanc
Dalle 294948 | Rez-de-Jardin | Pavés extérieur14 | 294948 | -746779066 | 15 | 02 | Rez-de-Jardin | par trois points | 1.64389 | -178.4 | -178.4 | -192 | Rez-de-Jardin (Rez-de-Jardin 15545) | 113 | <aucun> | 3554.4 | 639800 | 12800000 | Blanc | 12795360 | 639768 | 3553.57 | ...de matériaux et couleurs = Blanc; ...de stratigraphies = Dalle en béton armé; ...de matériaux et couleurs - 1 = Blanc; ...de matériaux et couleurs - 2 = Blanc
Dalle 294958 | Rez-de-Jardin | Pavés extérieur24 | 294958 | -746779066 | 25 | 02 | Rez-de-Jardin | par trois points | 0.0926996 | -185.4 | -184.9 | -184.4 | Rez-de-Jardin (Rez-de-Jardin 15545) | 106 | <aucun> | 3089.4 | 354500 | 7090000 | Blanc | 7090799 | 354540 | 3089.4 | ...de matériaux et couleurs = Blanc; ...de stratigraphies = Dalle en béton armé; ...de matériaux et couleurs - 1 = Blanc; ...de matériaux et couleurs - 2 = Blanc
Dalle 294957 | Rez-de-Jardin | Pavés extérieur23 | 294957 | -746779066 | 24 | 02 | Rez-de-Jardin | par trois points | 0.489623 | -179.4 | -184.4 | -185.4 | Rez-de-Jardin (Rez-de-Jardin 15545) | 112 | <aucun> | 3928.2 | 741600 | 14830000 | Blanc | 14832468 | 741623 | 3928.22 | ...de matériaux et couleurs = Blanc; ...de stratigraphies = Dalle en béton armé; ...de matériaux et couleurs - 1 = Blanc; ...de matériaux et couleurs - 2 = Blanc
Dalle 294956 | Rez-de-Jardin | Pavés extérieur22 | 294956 | -746779066 | 23 | 02 | Rez-de-Jardin | par trois points | 0.998565 | -179.4 | -185.4 | -178.9 | Rez-de-Jardin (Rez-de-Jardin 15545) | 112 | <aucun> | 3009.2 | 327000 | 6540000 | Blanc | 6539151 | 326958 | 3009.15 | ...de matériaux et couleurs = Blanc; ...de stratigraphies = Dalle en béton armé; ...de matériaux et couleurs - 1 = Blanc; ...de matériaux et couleurs - 2 = Blanc
Dalle 294959 | Rez-de-Jardin | Pavés extérieur25 | 294959 | -746779066 | 26 | 02 | Rez-de-Jardin | horizontal | 0 | -184.9 | -184.9 | -184.9 | Rez-de-Jardin (Rez-de-Jardin 15545) | 106.5 | <aucun> | 1689 | 137300 | 2750000 | Blanc | 2746654 | 137333 | 1689.04 | ...de matériaux et couleurs = Blanc; ...de stratigraphies = Dalle en béton armé; ...de matériaux et couleurs - 1 = Blanc; ...de matériaux et couleurs - 2 = Blanc
Dalle 294962 | Rez-de-Jardin | Pavés extérieur28 | 294962 | -746779066 | 29 | 02 | Rez-de-Jardin | horizontal | 0 | -184.9 | -184.9 | -184.9 | Rez-de-Jardin (Rez-de-Jardin 15545) | 106.5 | <aucun> | 3609.7 | 542700 | 10850000 | Blanc | 10854169 | 542708 | 3609.74 | ...de matériaux et couleurs = Blanc; ...de stratigraphies = Dalle en béton armé; ...de matériaux et couleurs - 1 = Blanc; ...de matériaux et couleurs - 2 = Blanc
Dalle 294961 | Rez-de-Jardin | Pavés extérieur27 | 294961 | -746779066 | 28 | 02 | Rez-de-Jardin | par trois points | 0.613592 | -183.4 | -184.2 | -184.9 | Rez-de-Jardin (Rez-de-Jardin 15545) | 108 | <aucun> | 2410.8 | 276000 | 5520000 | Blanc | 5519378 | 275969 | 2410.78 | ...de matériaux et couleurs = Blanc; ...de stratigraphies = Dalle en béton armé; ...de matériaux et couleurs - 1 = Blanc; ...de matériaux et couleurs - 2 = Blanc
Dalle 294960 | Rez-de-Jardin | Pavés extérieur26 | 294960 | -746779066 | 27 | 02 | Rez-de-Jardin | horizontal | 0 | -184.9 | -184.9 | -184.9 | Rez-de-Jardin (Rez-de-Jardin 15545) | 106.5 | <aucun> | 1854 | 189100 | 3780000 | Blanc | 3781291 | 189065 | 1854 | ...de matériaux et couleurs = Blanc; ...de stratigraphies = Dalle en béton armé; ...de matériaux et couleurs - 1 = Blanc; ...de matériaux et couleurs - 2 = Blanc
Dalle 294951 | Rez-de-Jardin | Pavés extérieur17 | 294951 | -746779066 | 18 | 02 | Rez-de-Jardin | par trois points | 0.409317 | -183.4 | -183.4 | -179.3 | Rez-de-Jardin (Rez-de-Jardin 15545) | 108 | <aucun> | 4080.3 | 976300 | 19530000 | Blanc | 19526010 | 976301 | 4080.31 | ...de matériaux et couleurs = Blanc; ...de stratigraphies = Dalle en béton armé; ...de matériaux et couleurs - 1 = Blanc; ...de matériaux et couleurs - 2 = Blanc
Dalle 294950 | Rez-de-Jardin | Pavés extérieur16 | 294950 | -746779066 | 17 | 02 | Rez-de-Jardin | par trois points | 1.60841 | -179.3 | -183.4 | -189.1 | Rez-de-Jardin (Rez-de-Jardin 15545) | 112.1 | <aucun> | 2549.3 | 223900 | 4480000 | Blanc | 4478242 | 223912 | 2549.29 | ...de matériaux et couleurs = Blanc; ...de stratigraphies = Dalle en béton armé; ...de matériaux et couleurs - 1 = Blanc; ...de matériaux et couleurs - 2 = Blanc
Dalle 294949 | Rez-de-Jardin | Pavés extérieur15 | 294949 | -746779066 | 16 | 02 | Rez-de-Jardin | par trois points | 1.75099 | -187.3 | -177.3 | -183.4 | Rez-de-Jardin (Rez-de-Jardin 15545) | 104.1 | <aucun> | 2136.3 | 210900 | 4220000 | Blanc | 4218676 | 210934 | 2136.01 | ...de matériaux et couleurs = Blanc; ...de stratigraphies = Dalle en béton armé; ...de matériaux et couleurs - 1 = Blanc; ...de matériaux et couleurs - 2 = Blanc
Dalle 294952 | Rez-de-Jardin | Pavés extérieur18 | 294952 | -746779066 | 19 | 02 | Rez-de-Jardin | par trois points | 1.68556 | -179.3 | -178.8 | -183.4 | Rez-de-Jardin (Rez-de-Jardin 15545) | 112.1 | <aucun> | 2614.6 | 181100 | 3620000 | Blanc | 3621771 | 181089 | 2614.57 | ...de matériaux et couleurs = Blanc; ...de stratigraphies = Dalle en béton armé; ...de matériaux et couleurs - 1 = Blanc; ...de matériaux et couleurs - 2 = Blanc
Dalle 294955 | Rez-de-Jardin | Pavés extérieur21 | 294955 | -746779066 | 22 | 02 | Rez-de-Jardin | par trois points | 0.0501195 | -179.4 | -179.4 | -178.9 | Rez-de-Jardin (Rez-de-Jardin 15545) | 112 | <aucun> | 4084.5 | 1029300 | 20590000 | Blanc | 20586846 | 1029342 | 4084.48 | ...de matériaux et couleurs = Blanc; ...de stratigraphies = Dalle en béton armé; ...de matériaux et couleurs - 1 = Blanc; ...de matériaux et couleurs - 2 = Blanc
Dalle 294954 | Rez-de-Jardin | Pavés extérieur20 | 294954 | -746779066 | 21 | 02 | Rez-de-Jardin | par trois points | 0.0699394 | -179.4 | -178.9 | -178.9 | Rez-de-Jardin (Rez-de-Jardin 15545) | 112 | <aucun> | 2605.5 | 184900 | 3700000 | Blanc | 3698863 | 184943 | 2605.46 | ...de matériaux et couleurs = Blanc; ...de stratigraphies = Dalle en béton armé; ...de matériaux et couleurs - 1 = Blanc; ...de matériaux et couleurs - 2 = Blanc
Dalle 294953 | Rez-de-Jardin | Pavés extérieur19 | 294953 | -746779066 | 20 | 02 | Rez-de-Jardin | par trois points | 0.0645183 | -178.9 | -179.4 | -179.3 | Rez-de-Jardin (Rez-de-Jardin 15545) | 112.5 | <aucun> | 2422.4 | 306400 | 6130000 | Blanc | 6127758 | 306388 | 2422.43 | ...de matériaux et couleurs = Blanc; ...de stratigraphies = Dalle en béton armé; ...de matériaux et couleurs - 1 = Blanc; ...de matériaux et couleurs - 2 = Blanc
Dalle 396734 | Rez-de-chaussée | Parvis entrée RDC | 396734 | -746779066 | 33 | 03 | Rez-de-chaussée | horizontal | 0 | 0 | 0 | 0 | Rez-de-chaussée (Rez-de-chaussée 1047) | 0 | <aucun> | 2444.5 | 202200 | 4040000 | Blanc | 4044571 | 202229 | 2444.53 | ...de matériaux et couleurs = Blanc; ...de stratigraphies = Dalle en béton armé; ...de matériaux et couleurs - 1 = Blanc; ...de matériaux et couleurs - 2 = Blanc
Dalle 322633 | Rez-de-chaussée | sol entrée bas RDC | 322633 | -746779066 | 32 | 03 | Rez-de-chaussée | par trois points | 1.76209 | -103.7 | -106.5 | -106.5 | Rez-de-chaussée (Rez-de-chaussée 1047) | 0.0153862 | sous RDC | 764.2 | 33600 | 670000 | Blanc | 672071 | 33603.6 | 764.236 | ...de matériaux et couleurs = Blanc; ...de stratigraphies = Dalle en béton armé; ...de matériaux et couleurs - 1 = Blanc; ...de matériaux et couleurs - 2 = Blanc
Dalle 1533996 | Niveau 2 | Dalle | 1533996 | -746779066 | 37 | 05 | Niveau 2 | horizontal | 0 | 853.91 | 853.91 | 853.91 | Niveau 2 (Niveau 2 13545) | 0 | <aucun> | 786.8 | 38600 | 770000 | Blanc | 771537 | 38576.8 | 786.808 | ...de matériaux et couleurs = Blanc; ...de stratigraphies = Dalle en béton armé; ...de matériaux et couleurs - 1 = Blanc; ...de matériaux et couleurs - 2 = Blanc

# IfcSlab: Plancher en brique-ciment 290 (7)
Type - Material: Carreaux en céramique 1.5 cm, Chape ordinaire 4 cm, Dalle plane terre-cuite-ciment isolée 22.5 cm, Enduit intérieur 1 cm
__RECOGNIZE__ - TPLG: 865; TPLG_OD: 9009; GENERATE: 1
CTLG_EXTERNAL_LINK - 0, DocType: 2; 0, Tag: 0; 0, Crc: -846697749; 1, DocType: 2; 1, Tag: 1; 1, Crc: -846697749; 2, DocType: 2; 2, Tag: 2; 2, Crc: -846697749; 3, DocType: 9; 3, Tag: 0; 3, Crc: -865865876
IFC_PSET_PolygonOffset - polygonOffsetFactor: 2; polygonOffsetUnits: 2
IFC_Pset_Alignment - Alignment: 1
IFC_Pset_Caractéristiques - Stratigraphie: Plancher en brique-ciment [290,00]; Épaisseur: 29 cm
IFC_Pset_Caractéristiques_Courbe - Présent: no; Orthogonal Pente: no
IFC_Pset_Géométrie_PENTE - Type de définition: horizontal; Pente: 0
IFC_Pset_Matériaux - Face supérieure: Orange saumon; Face inférieure: Orange saumon; Face latérale: Orange saumon
Pset_SlabCommon - Reference: Plancher en brique-ciment [290,00] (..\HORIZONTALES\Plancher en brique-ciment\Plancher brique-ciment\)
BaseQuantities - NominalWidth: 29 cm
Group: ...de matériaux et couleurs = Orange saumon; ...de matériaux et couleurs - 1 = Orange saumon; ...de matériaux et couleurs - 2 = Orange saumon; ...de stratigraphies = Plancher en brique-ciment
Name | In | Description = Nom | __RECOGNIZE__, ID = IFC_Pset_Caractéristiques, ID | Numérotation | Numéro niveau | Titre niveau | Cote Point 1 (cm) = Cote Point 2 (cm) = Cote Point 3 (cm) | NIVEAU | delta (cm) | sous Niveau | Périmètre (cm) | Surface (cm2) | Volume (cm3) | GrossVolume (cm3) | NetVolume (cm3) | GrossArea (cm2) | NetArea (cm2) | Perimeter (cm)
Enveloppe horizontale 303680 | Rez-de-Jardin | Sol entrée | 303680 | 10 | 02 | Rez-de-Jardin | -291.4 | Rez-de-Jardin (Rez-de-Jardin 15545) | 0 | <aucun> | 928.6 | 49300 | 1430000 | 1429231 | 1429231 | 49283.8 | 49283.8 | 928.616
Enveloppe horizontale 73501 | Rez-de-Jardin | Enveloppe horizontale | 73501 | 04 | 02 | Rez-de-Jardin | -291.4 | Rez-de-Jardin (Rez-de-Jardin 15545) | 0 | <aucun> | 12019 | 4737700 | 137390000 | 137393519 | 137393519 | 4737708 | 4737708 | 12018.6
Enveloppe horizontale 14691 | Rez-de-chaussée | sol RDC bas | 14691 | 03 | 03 | Rez-de-chaussée | -101.715 | Rez-de-chaussée (Rez-de-chaussée 1047) | 2 | sous RDC | 745.5 | 34700 | 1010000 | 1006702 | 1006702 | 34713.9 | 34713.9 | 745.483
Enveloppe horizontale 5567 | Rez-de-chaussée | sol RDC | 5567 | 01 | 03 | Rez-de-chaussée | 0 | Rez-de-chaussée (Rez-de-chaussée 1047) | 0 | <aucun> | 10272.6 | 3644300 | 105680000 | 105683823 | 105509227 | 3644270 | 3638249 | 10616.4
Enveloppe horizontale 567347 | Niveau 1 | Enveloppe horizontale | 567347 | 11 | 04 | Niveau 1 | 477.795 | Niveau 1 (Niveau 1 2343) | 0 | <aucun> | 9675.4 | 3768900 | 109300000 | 109299143 | 109299143 | 3768936 | 3768936 | 9675.4
Enveloppe horizontale 567348 | Niveau 2 | Enveloppe horizontale | 567348 | 12 | 05 | Niveau 2 | 856.41 | Niveau 2 (Niveau 2 13545) | 2.5 | <aucun> | 9840.1 | 3653100 | 105940000 | 105938603 | 105938603 | 3653055 | 3653055 | 9840.09
Enveloppe horizontale 1793902 | Mezzanine | Enveloppe horizontale | 1793902 | 14 | 06 | Mezzanine | 1198.91 | Mezzanine (Mezzanine 49003) | 110 | <aucun> | 896.2 | 41900 | 1220000 | 1214157 | 1214157 | 41867.5 | 41867.5 | 896.204

# IfcSlab: default 100, Enveloppe horizontale 303634
In: Rez-de-Jardin
Type - Material: <aucun> 10 cm
Description: Enveloppe horizontale; Group: ...de stratigraphies = default; ...de matériaux et couleurs = Orange saumon; ...de matériaux et couleurs - 1 = Orange saumon; ...de matériaux et couleurs - 2 = Orange saumon
__RECOGNIZE__ - ID: 303634; TPLG: 865; TPLG_OD: 9009; GENERATE: 1
CTLG_EXTERNAL_LINK - 0, DocType: 2; 0, Tag: 0; 0, Crc: -846697749; 1, DocType: 2; 1, Tag: 1; 1, Crc: -846697749; 2, DocType: 2; 2, Tag: 2; 2, Crc: -846697749; 3, DocType: 9; 3, Tag: 0; 3, Crc: -735948535
IFC_PSET_PolygonOffset - polygonOffsetFactor: 2; polygonOffsetUnits: 2
IFC_Pset_Alignment - Alignment: 1
IFC_Pset_Caractéristiques - ID: 303634; Numérotation: 09; Numéro niveau: 02; Titre niveau: Rez-de-Jardin; Nom: Enveloppe horizontale; Stratigraphie: default [100,00]; Épaisseur: 10 cm
IFC_Pset_Caractéristiques_Courbe - Présent: no; Orthogonal Pente: no
IFC_Pset_Géométrie_PENTE - Type de définition: horizontal; Pente: 0; Cote Point 1: -134.9 cm; Cote Point 2: -134.9 cm; Cote Point 3: -134.9 cm
IFC_Pset_Système de Référence Altimétrique_INFÉRIEUR - NIVEAU: Rez-de-Jardin (Rez-de-Jardin 15545); delta: 156.5 cm; sous Niveau: <aucun>
IFC_Pset_Données Métré - Périmètre: 574.3 cm; Surface: 12700 cm2; Volume: 130000 cm3
IFC_Pset_Matériaux - Face supérieure: Orange saumon; Face inférieure: Orange saumon; Face latérale: Orange saumon
Pset_SlabCommon - Reference: default [100,00] (..\HORIZONTALES\Default\)
BaseQuantities - GrossVolume: 127275 cm3; NetVolume: 127275 cm3; GrossArea: 12727.5 cm2; NetArea: 12727.5 cm2; Perimeter: 574.287 cm; NominalWidth: 10 cm

# IfcSlab: default 170, Enveloppe horizontale 198414
In: Mezzanine
Type - Material: <aucun> 17 cm
Description: sol mezzanine3; Group: ...de stratigraphies = default; ...de matériaux et couleurs = Orange saumon; ...de matériaux et couleurs - 1 = Orange saumon; ...de matériaux et couleurs - 2 = Orange saumon
__RECOGNIZE__ - ID: 198414; TPLG: 865; TPLG_OD: 9009; GENERATE: 1
CTLG_EXTERNAL_LINK - 0, DocType: 2; 0, Tag: 0; 0, Crc: -846697749; 1, DocType: 2; 1, Tag: 1; 1, Crc: -846697749; 2, DocType: 2; 2, Tag: 2; 2, Crc: -846697749; 3, DocType: 9; 3, Tag: 0; 3, Crc: 2096930987
IFC_PSET_PolygonOffset - polygonOffsetFactor: 2; polygonOffsetUnits: 2
IFC_Pset_Alignment - Alignment: 1
IFC_Pset_Caractéristiques - ID: 198414; Numérotation: 07; Numéro niveau: 06; Titre niveau: Mezzanine; Nom: sol mezzanine3; Stratigraphie: default [170,00]; Épaisseur: 17 cm
IFC_Pset_Caractéristiques_Courbe - Présent: no; Orthogonal Pente: no
IFC_Pset_Géométrie_PENTE - Type de définition: horizontal; Pente: 0; Cote Point 1: 1136.91 cm; Cote Point 2: 1136.91 cm; Cote Point 3: 1136.91 cm
IFC_Pset_Système de Référence Altimétrique_INFÉRIEUR - NIVEAU: Mezzanine (Mezzanine 49003); delta: 48 cm; sous Niveau: <aucun>
IFC_Pset_Données Métré - Périmètre: 1850.4 cm; Surface: 207700 cm2; Volume: 3530000 cm3
IFC_Pset_Matériaux - Face supérieure: Orange saumon; Face inférieure: Orange saumon; Face latérale: Orange saumon
Pset_SlabCommon - Reference: default [170,00] (..\HORIZONTALES\Default\)
BaseQuantities - GrossVolume: 3530424 cm3; NetVolume: 3530424 cm3; GrossArea: 207672 cm2; NetArea: 207672 cm2; Perimeter: 1850.36 cm; NominalWidth: 17 cm

# IfcSlab: default 177, Enveloppe horizontale 567349
In: Rez-de-Jardin
Type - Material: <aucun> 17.7 cm
Description: Enveloppe horizontale; Group: ...de stratigraphies = default; ...de matériaux et couleurs = Orange saumon; ...de matériaux et couleurs - 1 = Orange saumon; ...de matériaux et couleurs - 2 = Orange saumon
__RECOGNIZE__ - ID: 567349; TPLG: 865; TPLG_OD: 9009; GENERATE: 1
CTLG_EXTERNAL_LINK - 0, DocType: 2; 0, Tag: 0; 0, Crc: -846697749; 1, DocType: 2; 1, Tag: 1; 1, Crc: -846697749; 2, DocType: 2; 2, Tag: 2; 2, Crc: -846697749; 3, DocType: 9; 3, Tag: 0; 3, Crc: -727239942
IFC_PSET_PolygonOffset - polygonOffsetFactor: 2; polygonOffsetUnits: 2
IFC_Pset_Alignment - Alignment: 1
IFC_Pset_Caractéristiques - ID: 567349; Numérotation: 13; Numéro niveau: 02; Titre niveau: Rez-de-Jardin; Nom: Enveloppe horizontale; Stratigraphie: default [177,00]; Épaisseur: 17.7 cm
IFC_Pset_Caractéristiques_Courbe - Présent: no; Orthogonal Pente: no
IFC_Pset_Géométrie_PENTE - Type de définition: horizontal; Pente: 0; Cote Point 1: -184.4 cm; Cote Point 2: -184.4 cm; Cote Point 3: -184.4 cm
IFC_Pset_Système de Référence Altimétrique_INFÉRIEUR - NIVEAU: Rez-de-Jardin (Rez-de-Jardin 15545); delta: 107 cm; sous Niveau: <aucun>
IFC_Pset_Données Métré - Périmètre: 1574 cm; Surface: 138700 cm2; Volume: 2500000 cm3
IFC_Pset_Matériaux - Face supérieure: Orange saumon; Face inférieure: Orange saumon; Face latérale: Orange saumon
Pset_SlabCommon - Reference: default [177,00] (..\HORIZONTALES\Default\)
BaseQuantities - GrossVolume: 2454167 cm3; NetVolume: 2454167 cm3; GrossArea: 138653 cm2; NetArea: 138653 cm2; Perimeter: 1573.96 cm; NominalWidth: 17.7 cm

# IfcSlab: default 190, Dalle 1519592
In: Mezzanine
Type - Material: <aucun> 19 cm
Description: Dalle; Group: ...de matériaux et couleurs = Béton (01); ...de matériaux et couleurs - 1 = Béton (01); ...de matériaux et couleurs - 2 = Béton (01); ...de stratigraphies = default
__RECOGNIZE__ - ID: 1519592; TPLG: 249; TPLG_OD: 9003; GENERATE: 1
CTLG_EXTERNAL_LINK - 0, DocType: 2; 0, Tag: 0; 0, Crc: -1434640612; 1, DocType: 2; 1, Tag: 1; 1, Crc: -1434640612; 2, DocType: 2; 2, Tag: 2; 2, Crc: -1434640612; 3, DocType: 9; 3, Tag: 0; 3, Crc: 2121479351
IFC_PSET_PolygonOffset - polygonOffsetFactor: 2; polygonOffsetUnits: 2
IFC_Pset_Alignment - Alignment: 1
IFC_Pset_Caractéristiques - ID: 1519592; Numérotation: 36; Numéro niveau: 06; Titre niveau: Mezzanine; Nom: Dalle; Stratigraphie: default [190,00]; Épaisseur: 19 cm
IFC_Pset_Caractéristiques_Courbe - Présent: no; Orthogonal Pente: no
IFC_Pset_Géométrie_PENTE - Type de définition: horizontal; Pente: 0; Cote Point 1: 1015.91 cm; Cote Point 2: 1015.91 cm; Cote Point 3: 1015.91 cm
IFC_Pset_Système de Référence Altimétrique_INFÉRIEUR - NIVEAU: Mezzanine (Mezzanine 49003); delta: -73 cm; sous Niveau: <aucun>
IFC_Pset_Données Métré - Périmètre: 555.2 cm; Surface: 16100 cm2; Volume: 310000 cm3
IFC_Pset_Matériaux - Face supérieure: Béton (01); Face inférieure: Béton (01); Face latérale: Béton (01)
Pset_SlabCommon - Reference: default [190,00] (..\HORIZONTALES\Default\)
BaseQuantities - GrossVolume: 306259 cm3; NetVolume: 306259 cm3; GrossArea: 16118.9 cm2; NetArea: 16118.9 cm2; Perimeter: 555.244 cm; NominalWidth: 19 cm

# IfcSlab: default 200, Dalle 733377
In: Couverture
Type - Material: <aucun> 20 cm
Description: Dalle; Group: ...de matériaux et couleurs = Béton (01); ...de matériaux et couleurs - 1 = Béton (01); ...de matériaux et couleurs - 2 = Béton (01); ...de stratigraphies = default
__RECOGNIZE__ - ID: 733377; TPLG: 249; TPLG_OD: 9003; GENERATE: 1
CTLG_EXTERNAL_LINK - 0, DocType: 2; 0, Tag: 0; 0, Crc: -1434640612; 1, DocType: 2; 1, Tag: 1; 1, Crc: -1434640612; 2, DocType: 2; 2, Tag: 2; 2, Crc: -1434640612; 3, DocType: 9; 3, Tag: 0; 3, Crc: -1027595524
IFC_PSET_PolygonOffset - polygonOffsetFactor: 2; polygonOffsetUnits: 2
IFC_Pset_Alignment - Alignment: 1
IFC_Pset_Caractéristiques - ID: 733377; Numérotation: 35; Numéro niveau: 07; Titre niveau: Couverture; Nom: Dalle; Stratigraphie: default [200,00]; Épaisseur: 20 cm
IFC_Pset_Caractéristiques_Courbe - Présent: no; Orthogonal Pente: no
IFC_Pset_Géométrie_PENTE - Type de définition: horizontal; Pente: 0; Cote Point 1: 1223.61 cm; Cote Point 2: 1223.61 cm; Cote Point 3: 1223.61 cm
IFC_Pset_Système de Référence Altimétrique_INFÉRIEUR - NIVEAU: Couverture (Couverture 2134); delta: -145 cm; sous Niveau: <aucun>
IFC_Pset_Données Métré - Périmètre: 1326.6 cm; Surface: 96000 cm2; Volume: 1920000 cm3
IFC_Pset_Matériaux - Face supérieure: Béton (01); Face inférieure: Béton (01); Face latérale: Béton (01)
Pset_SlabCommon - Reference: default [200,00] (..\HORIZONTALES\Default\)
BaseQuantities - GrossVolume: 1920049 cm3; NetVolume: 1920049 cm3; GrossArea: 96002.5 cm2; NetArea: 96002.5 cm2; Perimeter: 1326.59 cm; NominalWidth: 20 cm

# IfcSlab: default 263 (2)
In: Mezzanine
Type - Material: <aucun> 26.3 cm
__RECOGNIZE__ - TPLG: 865; TPLG_OD: 9009; GENERATE: 1
CTLG_EXTERNAL_LINK - 0, DocType: 2; 0, Tag: 0; 0, Crc: -846697749; 1, DocType: 2; 1, Tag: 1; 1, Crc: -846697749; 2, DocType: 2; 2, Tag: 2; 2, Crc: -846697749; 3, DocType: 9; 3, Tag: 0; 3, Crc: 1048178519
IFC_PSET_PolygonOffset - polygonOffsetFactor: 2; polygonOffsetUnits: 2
IFC_Pset_Alignment - Alignment: 1
IFC_Pset_Caractéristiques - Numéro niveau: 06; Titre niveau: Mezzanine; Stratigraphie: default [263,00]; Épaisseur: 26.3 cm
IFC_Pset_Caractéristiques_Courbe - Présent: no; Orthogonal Pente: no
IFC_Pset_Géométrie_PENTE - Type de définition: horizontal; Pente: 0; Cote Point 1: 1088.91 cm; Cote Point 2: 1088.91 cm; Cote Point 3: 1088.91 cm
IFC_Pset_Système de Référence Altimétrique_INFÉRIEUR - NIVEAU: Mezzanine (Mezzanine 49003); delta: 0 cm; sous Niveau: <aucun>
IFC_Pset_Matériaux - Face supérieure: Orange saumon; Face inférieure: Orange saumon; Face latérale: Orange saumon
Pset_SlabCommon - Reference: default [263,00] (..\HORIZONTALES\Default\)
BaseQuantities - NominalWidth: 26.3 cm
Group: ...de stratigraphies = default; ...de matériaux et couleurs = Orange saumon; ...de matériaux et couleurs - 1 = Orange saumon; ...de matériaux et couleurs - 2 = Orange saumon
Name | Description = Nom | __RECOGNIZE__, ID = IFC_Pset_Caractéristiques, ID | Numérotation | Périmètre (cm) | Surface (cm2) | Volume (cm3) | GrossVolume (cm3) = NetVolume (cm3) | GrossArea (cm2) = NetArea (cm2) | Perimeter (cm)
Enveloppe horizontale 224669 | Enveloppe horizontale | 224669 | 08 | 2539.3 | 271100 | 7050000 | 7129548 | 271085 | 2539.28
Enveloppe horizontale 163039 | sol mezzanine1 | 163039 | 05 | 2650.7 | 291400 | 7580000 | 7664348 | 291420 | 2650.73

# IfcSlab: default 370, Enveloppe horizontale 192720
In: Mezzanine
Type - Material: <aucun> 37 cm
Description: sol mezzanine2; Group: ...de stratigraphies = default; ...de matériaux et couleurs = Orange saumon; ...de matériaux et couleurs - 1 = Orange saumon; ...de matériaux et couleurs - 2 = Orange saumon
__RECOGNIZE__ - ID: 192720; TPLG: 865; TPLG_OD: 9009; GENERATE: 1
CTLG_EXTERNAL_LINK - 0, DocType: 2; 0, Tag: 0; 0, Crc: -846697749; 1, DocType: 2; 1, Tag: 1; 1, Crc: -846697749; 2, DocType: 2; 2, Tag: 2; 2, Crc: -846697749; 3, DocType: 9; 3, Tag: 0; 3, Crc: -1906710360
IFC_PSET_PolygonOffset - polygonOffsetFactor: 2; polygonOffsetUnits: 2
IFC_Pset_Alignment - Alignment: 1
IFC_Pset_Caractéristiques - ID: 192720; Numérotation: 06; Numéro niveau: 06; Titre niveau: Mezzanine; Nom: sol mezzanine2; Stratigraphie: default [370,00]; Épaisseur: 37 cm
IFC_Pset_Caractéristiques_Courbe - Présent: no; Orthogonal Pente: no
IFC_Pset_Géométrie_PENTE - Type de définition: horizontal; Pente: 0; Cote Point 1: 1136.91 cm; Cote Point 2: 1136.91 cm; Cote Point 3: 1136.91 cm
IFC_Pset_Système de Référence Altimétrique_INFÉRIEUR - NIVEAU: Mezzanine (Mezzanine 49003); delta: 48 cm; sous Niveau: <aucun>
IFC_Pset_Données Métré - Périmètre: 1747.4 cm; Surface: 116900 cm2; Volume: 4330000 cm3
IFC_Pset_Matériaux - Face supérieure: Orange saumon; Face inférieure: Orange saumon; Face latérale: Orange saumon
Pset_SlabCommon - Reference: default [370,00] (..\HORIZONTALES\Default\)
BaseQuantities - GrossVolume: 4323478 cm3; NetVolume: 4323478 cm3; GrossArea: 116851 cm2; NetArea: 116851 cm2; Perimeter: 1747.36 cm; NominalWidth: 37 cm

# IfcSlab: default 400, Enveloppe horizontale 13222
In: Niveau 1
Type - Material: <aucun> 40 cm
Description: palier R1; Group: ...de stratigraphies = default; ...de matériaux et couleurs = Orange saumon; ...de matériaux et couleurs - 1 = Orange saumon; ...de matériaux et couleurs - 2 = Orange saumon
__RECOGNIZE__ - ID: 13222; TPLG: 865; TPLG_OD: 9009; GENERATE: 1
CTLG_EXTERNAL_LINK - 0, DocType: 2; 0, Tag: 0; 0, Crc: -846697749; 1, DocType: 2; 1, Tag: 1; 1, Crc: -846697749; 2, DocType: 2; 2, Tag: 2; 2, Crc: -846697749; 3, DocType: 9; 3, Tag: 0; 3, Crc: -1373787550
IFC_PSET_PolygonOffset - polygonOffsetFactor: 2; polygonOffsetUnits: 2
IFC_Pset_Alignment - Alignment: 1
IFC_Pset_Caractéristiques - ID: 13222; Numérotation: 02; Numéro niveau: 04; Titre niveau: Niveau 1; Nom: palier R1; Stratigraphie: default [400,00]; Épaisseur: 40 cm
IFC_Pset_Caractéristiques_Courbe - Présent: no; Orthogonal Pente: no
IFC_Pset_Géométrie_PENTE - Type de définition: horizontal; Pente: 0; Cote Point 1: 477.795 cm; Cote Point 2: 477.795 cm; Cote Point 3: 477.795 cm
IFC_Pset_Système de Référence Altimétrique_INFÉRIEUR - NIVEAU: Niveau 1 (Niveau 1 2343); delta: 0 cm; sous Niveau: <aucun>
IFC_Pset_Données Métré - Périmètre: 1244 cm; Surface: 78100 cm2; Volume: 3120000 cm3
IFC_Pset_Matériaux - Face supérieure: Orange saumon; Face inférieure: Orange saumon; Face latérale: Orange saumon
Pset_SlabCommon - Reference: default [400,00] (..\HORIZONTALES\Default\)
BaseQuantities - GrossVolume: 3124883 cm3; NetVolume: 3124883 cm3; GrossArea: 78122.1 cm2; NetArea: 78122.1 cm2; Perimeter: 1243.99 cm; NominalWidth: 40 cm

# IfcSlab: default 90, Dalle 449510
In: Niveau 1
Type - Material: <aucun> 9 cm
Description: Sol BALCON; Group: ...de matériaux et couleurs = Blanc; ...de matériaux et couleurs - 1 = Blanc; ...de matériaux et couleurs - 2 = Blanc; ...de stratigraphies = default
__RECOGNIZE__ - ID: 449510; TPLG: 249; TPLG_OD: 9003; GENERATE: 1
CTLG_EXTERNAL_LINK - 0, DocType: 2; 0, Tag: 0; 0, Crc: -746779066; 1, DocType: 2; 1, Tag: 1; 1, Crc: -746779066; 2, DocType: 2; 2, Tag: 2; 2, Crc: -746779066; 3, DocType: 9; 3, Tag: 0; 3, Crc: 1914036240
IFC_PSET_PolygonOffset - polygonOffsetFactor: 2; polygonOffsetUnits: 2
IFC_Pset_Alignment - Alignment: 1
IFC_Pset_Caractéristiques - ID: 449510; Numérotation: 34; Numéro niveau: 04; Titre niveau: Niveau 1; Nom: Sol BALCON; Stratigraphie: default [90,00]; Épaisseur: 9 cm
IFC_Pset_Caractéristiques_Courbe - Présent: no; Orthogonal Pente: no
IFC_Pset_Géométrie_PENTE - Type de définition: horizontal; Pente: 0; Cote Point 1: 477.795 cm; Cote Point 2: 477.795 cm; Cote Point 3: 477.795 cm
IFC_Pset_Système de Référence Altimétrique_INFÉRIEUR - NIVEAU: Niveau 1 (Niveau 1 2343); delta: 0 cm; sous Niveau: <aucun>
IFC_Pset_Données Métré - Périmètre: 2180.9 cm; Surface: 171000 cm2; Volume: 1540000 cm3
IFC_Pset_Matériaux - Face supérieure: Blanc; Face inférieure: Blanc; Face latérale: Blanc
Pset_SlabCommon - Reference: default [90,00] (..\HORIZONTALES\Default\)
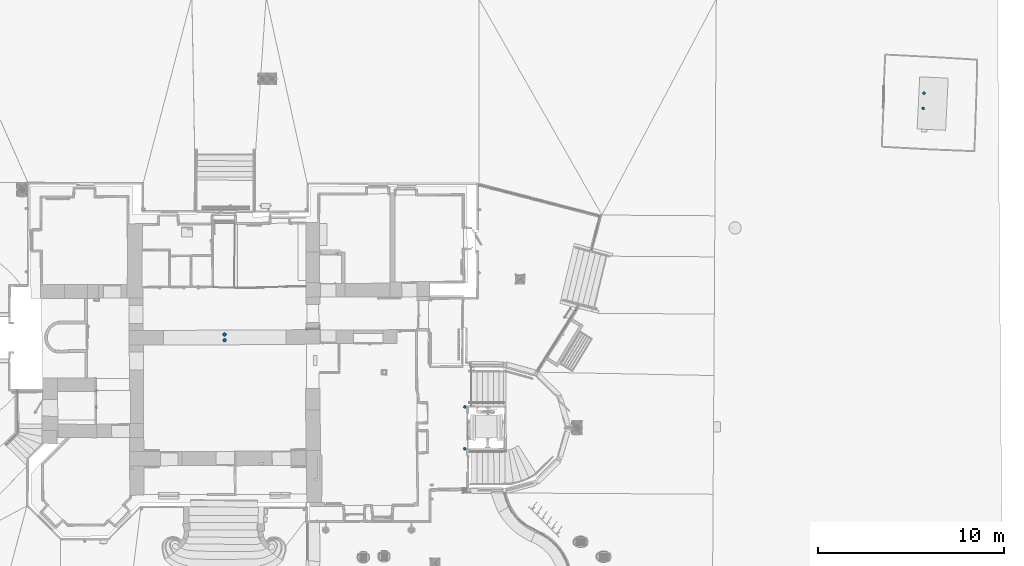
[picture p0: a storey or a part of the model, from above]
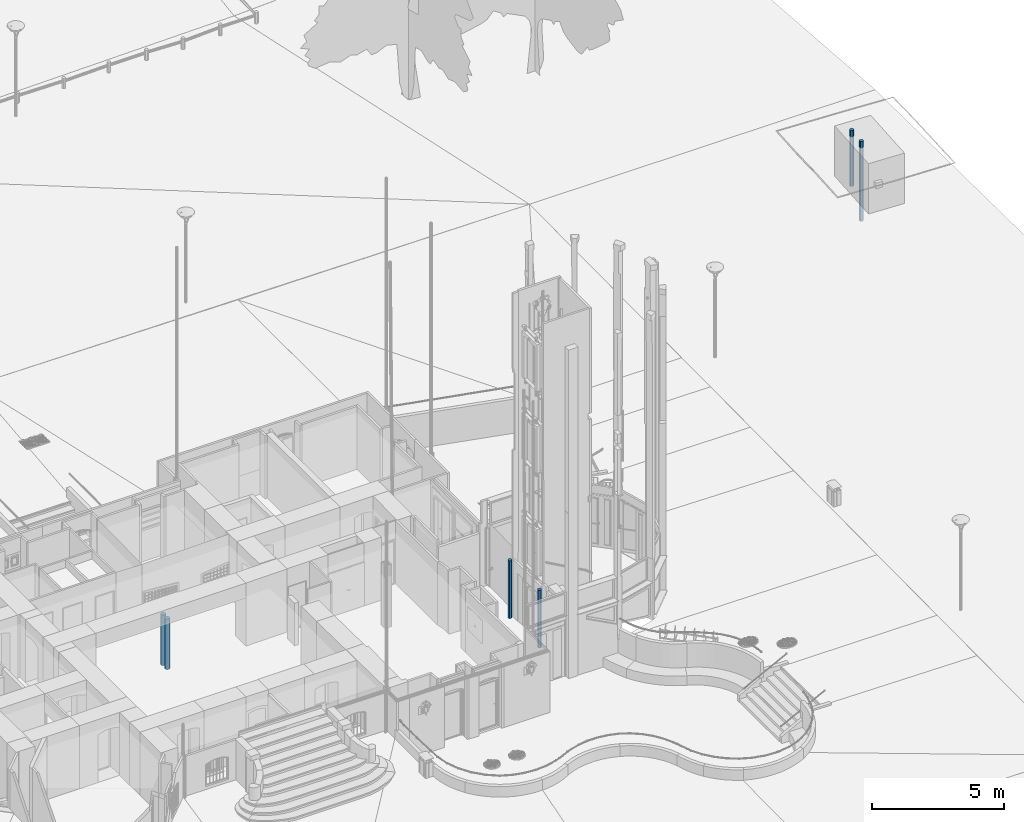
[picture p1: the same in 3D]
Properties of the parts of a building model (IFC2X3), part 18 of 37

# IfcSlab: default 90, Dalle 449510
BaseQuantities - GrossVolume: 1538900 cm3; NetVolume: 1538900 cm3; GrossArea: 170989 cm2; NetArea: 170989 cm2; Perimeter: 2180.93 cm; NominalWidth: 9 cm

# IfcStair (19)
__RECOGNIZE__ - TPLG: 140; TPLG_OD: 9013; GENERATE: 1
CTLG_EXTERNAL_LINK - 0, DocType: 2; 0, Tag: 1; 1, DocType: 2; 1, Tag: 2; 2, DocType: 2; 2, Tag: 3; 3, DocType: 2; 3, Tag: 4; 3, Crc: -990824515; 4, DocType: 2; 4, Tag: 5; 4, Crc: -459882616; 5, DocType: 2; 5, Tag: 6; 5, Crc: -990824515; 6, DocType: 2; 6, Tag: 7; 6, Crc: 913068333; 7, DocType: 2; 7, Tag: 8; 7, Crc: -623492449; 8, DocType: 2; 8, Tag: 9; 8, Crc: -623492449
IFC_PSET_PolygonOffset - polygonOffsetFactor: 2; polygonOffsetUnits: 2
IFC_Pset_Géométrie_REVÊTEMENT GIRON - Gche (saillie): 0 cm; Dte (saillie): 0 cm
IFC_Pset_Géométrie_REVÊTEMENT CONTREMARCHE - Épaisseur: 3 cm; Gche (saillie): 0 cm; Dte (saillie): 0 cm
IFC_Pset_Géométrie_DALLE PALIER - sets with these values: 2
IFC_Pset_Système de Référence Altimétrique_SUPÉRIEUR - sous Niveau: <aucun>
IFC_Pset_Matériaux - Structure Bois: Noyer 01; Marche Bois: Épicéa; Contremarche Bois: Noyer 01; Structure Métal: Aluminium mat; Marche Métal: Transparent; Contremarche Métal: Transparent
Name | In | __RECOGNIZE__, ID = IFC_Pset_Caractéristiques, ID | 0, Crc | 1, Crc | 2, Crc | Numérotation | Numéro niveau | Titre niveau | Type = Reference | Nombre de Contremarches | Hauteur contremarches (cm) = RiserHeight (cm) | IFC_Pset_Géométrie_REVÊTEMENT GIRON, Épaisseur (cm) | Front (saillie) (cm) | IFC_Pset_Géométrie_DALLE PALIER, Épaisseur (cm) | IFC_Pset_Géométrie_POUTRES, Base (section) (cm) = IFC_Pset_Géométrie_LIMON, Base (section) (cm) | Hauteur (coupe) (cm) | Nombre | IFC_Pset_Système de Référence Altimétrique_SUPÉRIEUR, NIVEAU | IFC_Pset_Système de Référence Altimétrique_SUPÉRIEUR, delta (cm) | IFC_Pset_Système de Référence Altimétrique_INFÉRIEUR, NIVEAU | IFC_Pset_Système de Référence Altimétrique_INFÉRIEUR, delta (cm) | sous Niveau | Volume de la Structure (cm3) | Surface des Girons (cm2) | Surface Contremarches (cm2) | Surface des Paliers (cm2) | Structure BA | Marche BA | Contremarche BA | NumberOfRiser | NumberOfTreads | TreadLength (cm) | Group
Escalier 294965 | Rez-de-Jardin | 294965 | 262804626 | 262804626 | 262804626 | 13 | 02 | Rez-de-Jardin | Béton Armé | 8 | 16.175 | 3 | 0 | 15 | 0 | 0 | 0 | HAUT Rez-de-Jardin (Rez-de-chaussée 1047) | -162 | Rez-de-Jardin (Rez-de-Jardin 15545) | 0 | <aucun> | 550000 | 27100 | 13700 | 0 | Gris béton | Gris béton | Gris béton | 7 | 7 | 27.7453 | ...de matériaux et couleurs = Gris béton; ...de matériaux et couleurs - 1 = Gris béton; ...de matériaux et couleurs - 2 = Gris béton; ...de matériaux et couleurs - 3 = Noyer 01; ...de matériaux et couleurs - 4 = Épicéa; ...de matériaux et couleurs - 5 = Noyer 01; ...de matériaux et couleurs - 6 = Aluminium mat; ...de matériaux et couleurs - 7 = Transparent; ...de matériaux et couleurs - 8 = Transparent
Escalier 322634 | Rez-de-Jardin | 322634 | -1434640612 | -1434640612 | -1434640612 | 14 | 02 | Rez-de-Jardin | Béton Armé | 5 | 16.6 | 5 | 1 | 15 | 0 | 0 | 0 | HAUT Rez-de-Jardin (Rez-de-chaussée 1047) | -106.4 | Rez-de-Jardin (Rez-de-Jardin 15545) | 102 | <aucun> | 460000 | 32500 | 14000 | 0 | Béton (01) | Béton (01) | Béton (01) | 4 | 4 | 30.4632 | ...de matériaux et couleurs - 3 = Noyer 01; ...de matériaux et couleurs - 4 = Épicéa; ...de matériaux et couleurs - 5 = Noyer 01; ...de matériaux et couleurs - 6 = Aluminium mat; ...de matériaux et couleurs - 7 = Transparent; ...de matériaux et couleurs - 8 = Transparent; ...de matériaux et couleurs = Béton (01); ...de matériaux et couleurs - 1 = Béton (01); ...de matériaux et couleurs - 2 = Béton (01)
Escalier 294723 | Rez-de-Jardin | 294723 | 262804626 | 262804626 | 262804626 | 12 | 02 | Rez-de-Jardin | Béton Armé | 7 | 15.5157 | 3 | 1.5 | 15 | 0 | 0 | 0 | HAUT Rez-de-Jardin (Rez-de-chaussée 1047) | -182.791 | Rez-de-Jardin (Rez-de-Jardin 15545) | 0 | <aucun> | 1080000 | 61100 | 26200 | 0 | Gris béton | Gris béton | Gris béton | 6 | 6 | 29.4981 | ...de matériaux et couleurs = Gris béton; ...de matériaux et couleurs - 1 = Gris béton; ...de matériaux et couleurs - 2 = Gris béton; ...de matériaux et couleurs - 3 = Noyer 01; ...de matériaux et couleurs - 4 = Épicéa; ...de matériaux et couleurs - 5 = Noyer 01; ...de matériaux et couleurs - 6 = Aluminium mat; ...de matériaux et couleurs - 7 = Transparent; ...de matériaux et couleurs - 8 = Transparent
Escalier 345565 | Rez-de-Jardin | 345565 | -1434640612 | -1434640612 | -1434640612 | 15 | 02 | Rez-de-Jardin | Béton Armé | 11 | 16.3638 | 5.5 | 2 | 15 | 0 | 0 | 0 | HAUT Rez-de-Jardin (Rez-de-chaussée 1047) | 0.601827 | Rez-de-Jardin (Rez-de-Jardin 15545) | 112 | <aucun> | 4160000 | 190200 | 53100 | 0 | Béton (01) | Béton (01) | Béton (01) | 10 | 10 | 39.081 | ...de matériaux et couleurs - 3 = Noyer 01; ...de matériaux et couleurs - 4 = Épicéa; ...de matériaux et couleurs - 5 = Noyer 01; ...de matériaux et couleurs - 6 = Aluminium mat; ...de matériaux et couleurs - 7 = Transparent; ...de matériaux et couleurs - 8 = Transparent; ...de matériaux et couleurs = Béton (01); ...de matériaux et couleurs - 1 = Béton (01); ...de matériaux et couleurs - 2 = Béton (01)
Escalier 574859 | Rez-de-Jardin | 574859 | -1434640612 | 1066166322 | 1066166322 | 16 | 02 | Rez-de-Jardin | Béton Armé | 7 | 15.2857 | 3 | 0 | 15 | 0 | 0 | 0 | HAUT Rez-de-Jardin (Rez-de-chaussée 1047) | -184.4 | Rez-de-Jardin (Rez-de-Jardin 15545) | 0 | <aucun> | 670000 | 37200 | 16400 | 0 | Béton (01) | Carreau décoré (85) | Carreau décoré (85) | 6 | 6 | 29.6069 | ...de matériaux et couleurs - 3 = Noyer 01; ...de matériaux et couleurs - 4 = Épicéa; ...de matériaux et couleurs - 5 = Noyer 01; ...de matériaux et couleurs - 6 = Aluminium mat; ...de matériaux et couleurs - 7 = Transparent; ...de matériaux et couleurs - 8 = Transparent; ...de matériaux et couleurs = Béton (01); ...de matériaux et couleurs - 1 = Carreau décoré (85); ...de matériaux et couleurs - 2 = Carreau décoré (85)
Escalier 577826 | Rez-de-Jardin | 577826 | -1434640612 | 1066166322 | 1066166322 | 17 | 02 | Rez-de-Jardin | Béton Armé | 11 | 16.7637 | 3 | 0 | 15 | 0 | 0 | 0 | HAUT Rez-de-Jardin (Rez-de-chaussée 1047) | 0 | Rez-de-Jardin (Rez-de-Jardin 15545) | 107 | <aucun> | 1210000 | 63800 | 28400 | 0 | Béton (01) | Carreau décoré (85) | Carreau décoré (85) | 10 | 10 | 31.0264 | ...de matériaux et couleurs - 3 = Noyer 01; ...de matériaux et couleurs - 4 = Épicéa; ...de matériaux et couleurs - 5 = Noyer 01; ...de matériaux et couleurs - 6 = Aluminium mat; ...de matériaux et couleurs - 7 = Transparent; ...de matériaux et couleurs - 8 = Transparent; ...de matériaux et couleurs = Béton (01); ...de matériaux et couleurs - 1 = Carreau décoré (85); ...de matériaux et couleurs - 2 = Carreau décoré (85)
Escalier 92069 | Rez-de-Jardin | 92069 | -1434640612 | -1434640612 | -1434640612 | 03 | 02 | Rez-de-Jardin | Béton Armé | 7 | 15.4858 | 5 | 3 | 15 | 0 | 0 | 0 | HAUT Rez-de-Jardin (Rez-de-chaussée 1047) | -179 | Rez-de-Jardin (Rez-de-Jardin 15545) | 4 | <aucun> | 960000 | 64000 | 22000 | 0 | Béton (01) | Béton (01) | Béton (01) | 6 | 6 | 29.6318 | ...de matériaux et couleurs - 3 = Noyer 01; ...de matériaux et couleurs - 4 = Épicéa; ...de matériaux et couleurs - 5 = Noyer 01; ...de matériaux et couleurs - 6 = Aluminium mat; ...de matériaux et couleurs - 7 = Transparent; ...de matériaux et couleurs - 8 = Transparent; ...de matériaux et couleurs = Béton (01); ...de matériaux et couleurs - 1 = Béton (01); ...de matériaux et couleurs - 2 = Béton (01)
Escalier 135402 | Rez-de-Jardin | 135402 | -746779066 | 1141262141 | 2075944260 | 05 | 02 | Rez-de-Jardin | Béton Armé | 7 | 15.9143 | 3 | 1.5 | 15 | 0 | 0 | 0 | HAUT Rez-de-Jardin (Rez-de-chaussée 1047) | -180 | Rez-de-Jardin (Rez-de-Jardin 15545) | 50 | extérieur | 1100000 | 62800 | 27200 | 0 | Blanc | Brèche oniciata | Blanc apricena | 6 | 6 | 30.2702 | ...de matériaux et couleurs - 3 = Noyer 01; ...de matériaux et couleurs - 4 = Épicéa; ...de matériaux et couleurs - 5 = Noyer 01; ...de matériaux et couleurs - 6 = Aluminium mat; ...de matériaux et couleurs - 7 = Transparent; ...de matériaux et couleurs - 8 = Transparent; ...de matériaux et couleurs = Blanc; ...de matériaux et couleurs - 1 = Brèche oniciata; ...de matériaux et couleurs - 2 = Blanc apricena
Escalier 718692 | Rez-de-chaussée | 718692 | -746779066 | 1066166322 | 1066166322 | 18 | 03 | Rez-de-chaussée | Béton Armé | 28 | 17.0641 | 3 | 0 | 20 | 0 | 0 | 0 | HAUT Rez-de-chaussée (Niveau 1 2343) | 0.00000423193 | Rez-de-chaussée (Rez-de-chaussée 1047) | 0 | <aucun> | 5230000 | 168200 | 80400 | 43800 | Blanc | Carreau décoré (85) | Carreau décoré (85) | 27 | 26 | 30.948 | ...de matériaux et couleurs - 3 = Noyer 01; ...de matériaux et couleurs - 4 = Épicéa; ...de matériaux et couleurs - 5 = Noyer 01; ...de matériaux et couleurs - 6 = Aluminium mat; ...de matériaux et couleurs - 7 = Transparent; ...de matériaux et couleurs - 8 = Transparent; ...de matériaux et couleurs = Blanc; ...de matériaux et couleurs - 1 = Carreau décoré (85); ...de matériaux et couleurs - 2 = Carreau décoré (85)
Escalier 12888 | Rez-de-chaussée | 12888 | -746779066 | 1141262141 | 2075944260 | 01 | 03 | Rez-de-chaussée | Bois (sur poutres) | 29 | 16.4757 | 3 | 3 | 0 | 10 | 9 | 2 | HAUT Rez-de-chaussée (Niveau 1 2343) | 0 | Rez-de-chaussée (Rez-de-chaussée 1047) | 0 | <aucun> | 0 | 92400 | 42900 | 25100 | Blanc | Brèche oniciata | Blanc apricena | 28 | 26 | 26.3559 | ...de matériaux et couleurs - 3 = Noyer 01; ...de matériaux et couleurs - 4 = Épicéa; ...de matériaux et couleurs - 5 = Noyer 01; ...de matériaux et couleurs - 6 = Aluminium mat; ...de matériaux et couleurs - 7 = Transparent; ...de matériaux et couleurs - 8 = Transparent; ...de matériaux et couleurs = Blanc; ...de matériaux et couleurs - 1 = Brèche oniciata; ...de matériaux et couleurs - 2 = Blanc apricena
Escalier 14692 | Rez-de-chaussée | 14692 | 12224888 | 12224888 | 12224888 | 02 | 03 | Rez-de-chaussée | Béton Armé | 6 | 17.2859 | 3 | 2 | 15 | 0 | 0 | 0 | HAUT Rez-de-chaussée (Niveau 1 2343) | -477.795 | Rez-de-chaussée (Rez-de-chaussée 1047) | 0 | sous RDC | 580000 | 31700 | 15600 | 0 | Rouge asiago | Rouge asiago | Rouge asiago | 5 | 5 | 29.7828 | ...de matériaux et couleurs - 3 = Noyer 01; ...de matériaux et couleurs - 4 = Épicéa; ...de matériaux et couleurs - 5 = Noyer 01; ...de matériaux et couleurs - 6 = Aluminium mat; ...de matériaux et couleurs - 7 = Transparent; ...de matériaux et couleurs - 8 = Transparent; ...de matériaux et couleurs = Rouge asiago; ...de matériaux et couleurs - 1 = Rouge asiago; ...de matériaux et couleurs - 2 = Rouge asiago
Escalier 724676 | Niveau 1 | 724676 | -746779066 | 1066166322 | 1066166322 | 19 | 04 | Niveau 1 | Béton Armé | 22 | 17.2098 | 3 | 0 | 20 | 0 | 0 | 0 | HAUT Niveau 1 (Niveau 2 13545) | 2.50003 | Niveau 1 (Niveau 1 2343) | 0 | <aucun> | 4890000 | 127000 | 64800 | 80700 | Blanc | Carreau décoré (85) | Carreau décoré (85) | 21 | 20 | 30.4879 | ...de matériaux et couleurs - 3 = Noyer 01; ...de matériaux et couleurs - 4 = Épicéa; ...de matériaux et couleurs - 5 = Noyer 01; ...de matériaux et couleurs - 6 = Aluminium mat; ...de matériaux et couleurs - 7 = Transparent; ...de matériaux et couleurs - 8 = Transparent; ...de matériaux et couleurs = Blanc; ...de matériaux et couleurs - 1 = Carreau décoré (85); ...de matériaux et couleurs - 2 = Carreau décoré (85)
Escalier 133769 | Niveau 1 | 133769 | -746779066 | 1141262141 | 2075944260 | 04 | 04 | Niveau 1 | Bois (sur poutres) | 24 | 15.713 | 3 | 3 | 0 | 10 | 9 | 2 | HAUT Niveau 1 (Niveau 2 13545) | 0.998143 | Niveau 1 (Niveau 1 2343) | 0 | <aucun> | 0 | 77900 | 33800 | 35200 | Blanc | Brèche oniciata | Blanc apricena | 23 | 22 | 25.9982 | ...de matériaux et couleurs - 3 = Noyer 01; ...de matériaux et couleurs - 4 = Épicéa; ...de matériaux et couleurs - 5 = Noyer 01; ...de matériaux et couleurs - 6 = Aluminium mat; ...de matériaux et couleurs - 7 = Transparent; ...de matériaux et couleurs - 8 = Transparent; ...de matériaux et couleurs = Blanc; ...de matériaux et couleurs - 1 = Brèche oniciata; ...de matériaux et couleurs - 2 = Blanc apricena
Escalier 192784 | Niveau 2 | 192784 | -746779066 | 1141262141 | 2075944260 | 08 | 05 | Niveau 2 | Béton Armé | 13 | 21.853 | 3 | 3 | 15 | 0 | 0 | 0 | HAUT Mezzanine (Couverture 2134) | -230.613 | Niveau 2 (Niveau 2 13545) | 0 | <aucun> | 460000 | 20200 | 19200 | 0 | Blanc | Brèche oniciata | Blanc apricena | 12 | 12 | 18.6583 | ...de matériaux et couleurs - 3 = Noyer 01; ...de matériaux et couleurs - 4 = Épicéa; ...de matériaux et couleurs - 5 = Noyer 01; ...de matériaux et couleurs - 6 = Aluminium mat; ...de matériaux et couleurs - 7 = Transparent; ...de matériaux et couleurs - 8 = Transparent; ...de matériaux et couleurs = Blanc; ...de matériaux et couleurs - 1 = Brèche oniciata; ...de matériaux et couleurs - 2 = Blanc apricena
Escalier 184576 | Niveau 2 | 184576 | -746779066 | 1141262141 | 2075944260 | 06 | 05 | Niveau 2 | Béton Armé | 11 | 16.3636 | 4 | 1 | 15 | 0 | 0 | 0 | HAUT Niveau 2 (Mezzanine 49003) | -51.9104 | Niveau 2 (Niveau 2 13545) | 3.08963 | <aucun> | 430000 | 20200 | 14100 | 2200 | Blanc | Brèche oniciata | Blanc apricena | 10 | 10 | 18.9285 | ...de matériaux et couleurs - 3 = Noyer 01; ...de matériaux et couleurs - 4 = Épicéa; ...de matériaux et couleurs - 5 = Noyer 01; ...de matériaux et couleurs - 6 = Aluminium mat; ...de matériaux et couleurs - 7 = Transparent; ...de matériaux et couleurs - 8 = Transparent; ...de matériaux et couleurs = Blanc; ...de matériaux et couleurs - 1 = Brèche oniciata; ...de matériaux et couleurs - 2 = Blanc apricena
Escalier 184577 | Niveau 2 | 184577 | -746779066 | 1141262141 | 2075944260 | 07 | 05 | Niveau 2 | Béton Armé | 3 | 18.3333 | 4 | 1 | 15 | 0 | 0 | 0 | HAUT Niveau 2 (Mezzanine 49003) | 3.08963 | Niveau 2 (Niveau 2 13545) | 183.09 | <aucun> | 90000 | 5400 | 4200 | 0 | Blanc | Brèche oniciata | Blanc apricena | 2 | 2 | 23.6681 | ...de matériaux et couleurs - 3 = Noyer 01; ...de matériaux et couleurs - 4 = Épicéa; ...de matériaux et couleurs - 5 = Noyer 01; ...de matériaux et couleurs - 6 = Aluminium mat; ...de matériaux et couleurs - 7 = Transparent; ...de matériaux et couleurs - 8 = Transparent; ...de matériaux et couleurs = Blanc; ...de matériaux et couleurs - 1 = Brèche oniciata; ...de matériaux et couleurs - 2 = Blanc apricena
Escalier 197960 | Mezzanine | 197960 | -746779066 | 1141262141 | 2075944260 | 11 | 06 | Mezzanine | Béton Armé | 3 | 15.3333 | 3 | 0 | 15 | 0 | 0 | 0 | HAUT Mezzanine (Couverture 2134) | -232.613 | Mezzanine (Mezzanine 49003) | 1.08963 | <aucun> | 160000 | 9800 | 5700 | 0 | Blanc | Brèche oniciata | Blanc apricena | 2 | 2 | 33.3209 | ...de matériaux et couleurs - 3 = Noyer 01; ...de matériaux et couleurs - 4 = Épicéa; ...de matériaux et couleurs - 5 = Noyer 01; ...de matériaux et couleurs - 6 = Aluminium mat; ...de matériaux et couleurs - 7 = Transparent; ...de matériaux et couleurs - 8 = Transparent; ...de matériaux et couleurs = Blanc; ...de matériaux et couleurs - 1 = Brèche oniciata; ...de matériaux et couleurs - 2 = Blanc apricena
Escalier 193050 | Mezzanine | 193050 | -746779066 | 1141262141 | 2075944260 | 10 | 06 | Mezzanine | Béton Armé | 4 | 15.5462 | 3 | 0 | 15 | 0 | 0 | 0 | HAUT Mezzanine (Couverture 2134) | -169.613 | Mezzanine (Mezzanine 49003) | 47.9048 | <aucun> | 460000 | 26600 | 15800 | 0 | Blanc | Brèche oniciata | Blanc apricena | 3 | 3 | 25.1216 | ...de matériaux et couleurs - 3 = Noyer 01; ...de matériaux et couleurs - 4 = Épicéa; ...de matériaux et couleurs - 5 = Noyer 01; ...de matériaux et couleurs - 6 = Aluminium mat; ...de matériaux et couleurs - 7 = Transparent; ...de matériaux et couleurs - 8 = Transparent; ...de matériaux et couleurs = Blanc; ...de matériaux et couleurs - 1 = Brèche oniciata; ...de matériaux et couleurs - 2 = Blanc apricena
Escalier 192842 | Mezzanine | 192842 | -746779066 | 1141262141 | 2075944260 | 09 | 06 | Mezzanine | Béton Armé | 3 | 16 | 3 | 0 | 15 | 0 | 0 | 0 | HAUT Mezzanine (Couverture 2134) | -230.613 | Mezzanine (Mezzanine 49003) | 1.08963 | <aucun> | 80000 | 4800 | 3500 | 0 | Blanc | Brèche oniciata | Blanc apricena | 2 | 2 | 28.8667 | ...de matériaux et couleurs - 3 = Noyer 01; ...de matériaux et couleurs - 4 = Épicéa; ...de matériaux et couleurs - 5 = Noyer 01; ...de matériaux et couleurs - 6 = Aluminium mat; ...de matériaux et couleurs - 7 = Transparent; ...de matériaux et couleurs - 8 = Transparent; ...de matériaux et couleurs = Blanc; ...de matériaux et couleurs - 1 = Brèche oniciata; ...de matériaux et couleurs - 2 = Blanc apricena

# IfcStairFlight (32)
__RECOGNIZE__ - TPLG: 2002; TPLG_OD: 2002; GENERATE: 0
Name | In | Material | ID | Reference | NumberOfRiser = NumberOfTreads | RiserHeight (cm) | TreadLength (cm)
4294967294 | Rez-de-Jardin | Gris béton | -2 | Élément Escalier 1 | 7 | 16.175 | 27.7453
4294967293 | Rez-de-Jardin | Béton (01) | -3 | Élément Escalier 1 | 4 | 16.6 | 30.4632
4294967291 | Rez-de-Jardin | Gris béton | -5 | Élément Escalier 1 | 6 | 15.5157 | 29.4981
4294967290 | Rez-de-Jardin | Béton (01) | -6 | Élément Escalier 1 | 10 | 16.3638 | 39.081
4294967279 | Rez-de-Jardin | Béton (01), Carreau décoré (85) | -17 | Élément Escalier 1 | 6 | 15.2857 | 29.6069
4294967278 | Rez-de-Jardin | Béton (01), Carreau décoré (85) | -18 | Élément Escalier 1 | 10 | 16.7637 | 31.0264
4294967276 | Rez-de-Jardin | Béton (01) | -20 | Élément Escalier 1 | 6 | 15.4858 | 29.6318
4294967264 | Rez-de-Jardin | Blanc, Blanc apricena, Brèche oniciata | -32 | Élément Escalier 1 | 6 | 15.9143 | 30.2702
4294967289 | Rez-de-chaussée | Blanc, Carreau décoré (85) | -7 | Élément Escalier 1 | 6 | 17.0641 | 29.2529
4294967288 | Rez-de-chaussée | Blanc, Carreau décoré (85) | -8 | Élément Escalier 2 | 7 | 17.0641 | 32.5495
4294967287 | Rez-de-chaussée | Blanc, Carreau décoré (85) | -9 | Élément Escalier 4 | 7 | 17.0641 | 31.6121
4294967286 | Rez-de-chaussée | Blanc, Carreau décoré (85) | -10 | Élément Escalier 5 | 6 | 17.0641 | 30
4294967271 | Rez-de-chaussée | Noyer 01, Épicéa | -25 | Élément Escalier 1 | 12 | 16.4757 | 27.086
4294967270 | Rez-de-chaussée | Noyer 01, Épicéa | -26 | Élément Escalier 3 | 3 | 16.4757 | 24.6511
4294967269 | Rez-de-chaussée | Noyer 01, Épicéa | -27 | Élément Escalier 5 | 11 | 16.4757 | 26.0243
4294967265 | Rez-de-chaussée | Rouge asiago | -31 | Élément Escalier 1 | 5 | 17.2859 | 29.7828
4294967284 | Niveau 1 | Blanc, Carreau décoré (85) | -12 | Élément Escalier 1 | 5 | 17.2098 | 29.8536
4294967283 | Niveau 1 | Blanc, Carreau décoré (85) | -13 | Élément Escalier 2 | 5 | 17.2098 | 31.0759
4294967282 | Niveau 1 | Blanc, Carreau décoré (85) | -14 | Élément Escalier 4 | 4 | 17.2098 | 31.2776
4294967281 | Niveau 1 | Blanc, Carreau décoré (85) | -15 | Élément Escalier 5 | 6 | 17.2098 | 30
4294967275 | Niveau 1 | Noyer 01, Épicéa | -21 | Élément Escalier 1 | 11 | 15.713 | 26.0214
4294967274 | Niveau 1 | Noyer 01, Épicéa | -22 | Élément Escalier 3 | 11 | 15.713 | 25.975
4294967263 | Niveau 2 | Blanc, Blanc apricena, Brèche oniciata | -33 | Élément Escalier 1 | 4 | 21.853 | 18.6583
4294967262 | Niveau 2 | Blanc, Blanc apricena, Brèche oniciata | -34 | Élément Escalier 2 | 4 | 21.853 | 18.6583
4294967261 | Niveau 2 | Blanc, Blanc apricena, Brèche oniciata | -35 | Élément Escalier 3 | 4 | 21.853 | 18.6583
4294967259 | Niveau 2 | Blanc, Blanc apricena, Brèche oniciata | -37 | Élément Escalier 1 | 3 | 16.3636 | 18.9285
4294967258 | Niveau 2 | Blanc, Blanc apricena, Brèche oniciata | -38 | Élément Escalier 2 | 3 | 16.3636 | 18.9285
4294967257 | Niveau 2 | Blanc, Blanc apricena, Brèche oniciata | -39 | Élément Escalier 3 | 4 | 16.3636 | 18.9285
4294967255 | Niveau 2 | Blanc, Blanc apricena, Brèche oniciata | -41 | Élément Escalier 1 | 2 | 18.3333 | 23.6681
4294967292 | Mezzanine | Blanc, Blanc apricena, Brèche oniciata | -4 | Élément Escalier 1 | 2 | 15.3333 | 33.3209
4294967277 | Mezzanine | Blanc, Blanc apricena, Brèche oniciata | -19 | Élément Escalier 1 | 3 | 15.5462 | 25.1216
4294967260 | Mezzanine | Blanc, Blanc apricena, Brèche oniciata | -36 | Élément Escalier 1 | 2 | 16 | 28.8667

# IfcTransportElement, Ascenseur 567343
In: Rez-de-Jardin
Material: MaterialNero intenso2, Acier inoxydable opaque, Blanc pur, Vert mai, Acier inoxydable brossé, Blanc, MaterialBottoniera_1, Aluminium mat, Mirroir, Gris aluminium, Blanc trafic, MaterialPulsantiera Interna 186x877, Blanc aluminium; Group: ...de matériaux et couleurs - 1 = Aluminium mat; ...de matériaux et couleurs - 2 = Aluminium mat; ...de matériaux et couleurs - 3 = Aluminium mat; ...de matériaux et couleurs = Aluminium mat; ...de blocs 3d = Moteur; ...de blocs 3d - 1 = AncoraGuida; ...de blocs 3d - 2 = AncoraAccessi; ...de blocs 3d - 3 = C6AA; ...de blocs 3d - 4 = BC3AA; ...de blocs 3d - 5 = Échelle; ...de blocs 3d - 6 = BP3BB; ...de blocs 3d - 7 = S1AA; ...de blocs 3d - 8 = Local macchine; ...de blocs 3d - 9 = IP6AA; ...de blocs 3d - 10 = Ancre de contrepoids; ...de blocs 3d - 11 = GancioTestata; ...de matériaux et couleurs - 4 = Aluminium mat; ...de matériaux et couleurs - 5 = Aluminium mat; ...de matériaux et couleurs - 6 = Blanc; ...de matériaux et couleurs - 7 = Blanc; ...de matériaux et couleurs - 8 = Aluminium mat; ...de matériaux et couleurs - 9 = Aluminium mat; ...de matériaux et couleurs - 10 = Vert mai; ...de matériaux et couleurs - 11 = Blanc aluminium; ...de matériaux et couleurs - 12 = Blanc trafic; ...de matériaux et couleurs - 13 = Gris aluminium; ...de matériaux et couleurs - 14 = Acier inoxydable opaque; ...de matériaux et couleurs - 15 = MaterialPulsantiera Interna 186x877; ...de matériaux et couleurs - 16 = Acier inoxydable brossé; ...de matériaux et couleurs - 17 = Gris aluminium; ...de matériaux et couleurs - 18 = MaterialBottoniera_1; ...de matériaux et couleurs - 19 = Acier inoxydable brossé; ...de matériaux et couleurs - 20 = Acier inoxydable brossé; ...de matériaux et couleurs - 21 = Mirroir; ...de matériaux et couleurs - 22 = MaterialNero intenso2; ...de matériaux et couleurs - 23 = Acier inoxydable brossé; ...de matériaux et couleurs - 24 = Blanc pur; ...de matériaux et couleurs - 25 = Blanc trafic; ...de matériaux et couleurs - 26 = Blanc trafic
__RECOGNIZE__ - ID: 567343; TPLG: 1701; TPLG_OD: 1701; GENERATE: 1
CTLG_EXTERNAL_LINK - 0, DocType: 12; 0, Tag: 10; 0, Crc: -2097065143; 1, DocType: 12; 1, Tag: 20; 1, Crc: 863636973; 2, DocType: 12; 2, Tag: 30; 2, Crc: 786017966; 3, DocType: 12; 3, Tag: 40; 3, Crc: 1927754278; 4, DocType: 12; 4, Tag: 50; 4, Crc: -441749195; 5, DocType: 12; 5, Tag: 60; 5, Crc: -1961964856; 6, DocType: 12; 6, Tag: 70; 6, Crc: -179599895; 7, DocType: 12; 7, Tag: 80; 7, Crc: -479926819; 8, DocType: 12; 8, Tag: 90; 8, Crc: -1835343071; 9, DocType: 12; 9, Tag: 100; 9, Crc: 2097928805; 10, DocType: 12; 10, Tag: 110; 10, Crc: -940310666; 11, DocType: 12; 11, Tag: 120; 11, Crc: 133774966; 12, DocType: 2; 12, Tag: 0; 12, Crc: 913068333; 13, DocType: 2; 13, Tag: 1; 13, Crc: 913068333; 14, DocType: 2; 14, Tag: 3; 14, Crc: 913068333; 15, DocType: 2; 15, Tag: 4; 15, Crc: 913068333; 16, DocType: 2; 16, Tag: 5; 16, Crc: 913068333; 17, DocType: 2; 17, Tag: 6; 17, Crc: 913068333; 18, DocType: 2; 18, Tag: 7; 18, Crc: -746779066; 19, DocType: 2; 19, Tag: 8; 19, Crc: -746779066; 20, DocType: 2; 20, Tag: 9; 20, Crc: 913068333; 21, DocType: 2; 21, Tag: 11; 21, Crc: 913068333; 22, DocType: 2; 22, Tag: 110; 22, Crc: 1027760004; 23, DocType: 2; 23, Tag: 111; 23, Crc: 722360325; 24, DocType: 2; 24, Tag: 120; 24, Crc: -1731763687; 25, DocType: 2; 25, Tag: 130; 25, Crc: -1611473673; 26, DocType: 2; 26, Tag: 140; 26, Crc: -72692602; 27, DocType: 2; 27, Tag: 150; 27, Crc: 1007332597; 28, DocType: 2; 28, Tag: 151; 28, Crc: 1792517069; 29, DocType: 2; 29, Tag: 160; 29, Crc: -1611473673; 30, DocType: 2; 30, Tag: 170; 30, Crc: -1570116034; 31, DocType: 2; 31, Tag: 171; 31, Crc: 1792517069; 32, DocType: 2; 32, Tag: 180; 32, Crc: 1792517069; 33, DocType: 2; 33, Tag: 181; 33, Crc: 49598867; 34, DocType: 2; 34, Tag: 200; 34, Crc: -843551026; 35, DocType: 2; 35, Tag: 201; 35, Crc: 1792517069; 36, DocType: 2; 36, Tag: 202; 36, Crc: -1697816127; 37, DocType: 2; 37, Tag: 210; 37, Crc: -1731763687; 38, DocType: 2; 38, Tag: 211; 38, Crc: -1731763687
IFC_PSET_PolygonOffset - polygonOffsetFactor: 2; polygonOffsetUnits: 2
IFC_Pset_Caractéristiques - ID: 567343; Numérotation: 01; Numéro niveau: 02; Titre niveau: Rez-de-Jardin; Nombre d'étages: 5; Arrêt ascenseur: 1; Hauteur cage: 1614.9 cm; Type ascenseur: Câble
IFC_Pset_Géométrie_Cage - Largeur pièce: 220 cm; Profondeur pièce: 195.741 cm; Hauteur dernier étage: 342 cm; Hauteur fosse: 110 cm
IFC_Pset_Géométrie_Cabine - Largeur cabine: 120 cm; Profondeur cabine: 111.741 cm; Hauteur cabina: 230 cm; Parois avec accès à la cabine: frontal, arrière
IFC_Pset_Géométrie_Accès - Hauteur accesso: 200 cm; Largeur accès: 83 cm; Type ouverture porte: Latérale; Pourcentage ouverture porte: 0
IFC_Pset_Système de Référence Altimétrique_INFÉRIEUR - NIVEAU: Rez-de-Jardin (Rez-de-Jardin 15545); delta: 4.44089e-14 cm; sous Niveau: <aucun>
IFC_Pset_Données Métré - Surface de la cage: 43100 cm2
IFC_Pset_Matériaux - Remplissage: Aluminium mat; Matériau de la cabine: Aluminium mat; Matériau de la porte: Aluminium mat; Matériau du cadre de la porte: Aluminium mat; Matériau du contrepoids: Aluminium mat; Matériau du moteur: Aluminium mat; Matériau de l'escalier: Aluminium mat; Matériau de l'intérieur de la cabine: Blanc; Matériau du plancher de la cabine: Blanc; Matériau de la structure de l'ascenseur: Aluminium mat

# IfcWall: default 0.101999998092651 (31)
Type - Material: <aucun> 0.0102 cm
Description: _INVF_Enveloppe fantôme; Group: ...de stratigraphies = default; ...de matériaux et couleurs = Enveloppe fantôme
__RECOGNIZE__ - TPLG: 442; TPLG_OD: 9002; GENERATE: 1
CTLG_EXTERNAL_LINK - 0, DocType: 2; 0, Tag: 0; 0, Crc: 11150925; 1, DocType: 9; 1, Tag: 0; 1, Crc: -889747670
IFC_PSET_PolygonOffset - polygonOffsetFactor: 2; polygonOffsetUnits: 2
IFC_Pset_Alignment - Alignment: 2
IFC_Pset_Strat_Detail_Align - ExternalFace: 0
IFC_Pset_Système de Référence Altimétrique_INFÉRIEUR - sous Niveau: <aucun>
IFC_Pset_Matériaux - Principal: Enveloppe fantôme
Pset_WallCommon - Reference: default [0,10] (..\VERTICALES\Default\)
BaseQuantities - NominalWidth: 0.0102 cm
Name | In | __RECOGNIZE__, ID = IFC_Pset_Caractéristiques, ID | Numérotation | Numéro niveau | Titre niveau | Forme en Élévation | Longueur (cm) = NominalLength (cm) | IFC_Pset_Géométrie, Hauteur (cm) | IFC_Pset_Géométrie, Cote (cm) = IFC_Pset_Géométrie_P1 (POINT initial), Cote (cm) = IFC_Pset_Géométrie_P2 (POINT final), Cote (cm) = IFC_Pset_Système de Référence Altimétrique_INFÉRIEUR, delta (cm) = IFC_Pset_Système de Référence Altimétrique_INFÉRIEUR, delta (P1) (cm) = IFC_Pset_Système de Référence Altimétrique_INFÉRIEUR, delta (P2) (cm) | IFC_Pset_Géométrie_P1 (POINT initial), Hauteur (cm) | IFC_Pset_Géométrie_P1 (POINT initial), Angle XY (deg) | IFC_Pset_Géométrie_P2 (POINT final), Hauteur (cm) | IFC_Pset_Géométrie_P2 (POINT final), Angle XY (deg) | IFC_Pset_Système de Référence Altimétrique_SUPÉRIEUR, NIVEAU | IFC_Pset_Système de Référence Altimétrique_SUPÉRIEUR, delta (cm) = IFC_Pset_Système de Référence Altimétrique_SUPÉRIEUR, delta (P1) (cm) = IFC_Pset_Système de Référence Altimétrique_SUPÉRIEUR, delta (P2) (cm) | sous Niveau | IFC_Pset_Système de Référence Altimétrique_INFÉRIEUR, NIVEAU | Longueur Pied (cm) | Longueur Tête (cm) | Hauteur Maximale (cm) | Hauteur Minimale (cm) | Surface (cm2) | GrossVolume (cm3) = NetVolume (cm3) | NominalHeight (cm) | GrossFootprintArea (cm2) = NetFootprintArea (cm2) | GrossSideArea (cm2) = NetSideArea (cm2)
Enveloppe fantôme 778370 | Rez-de-Jardin | 778370 | 21 | 02 | Rez-de-Jardin | rectangle | 207.803 | 291.413 | 0 | 291.413 | 89.3256 | 291.413 | 269.326 | HAUT Rez-de-Jardin (Rez-de-chaussée 1047) | 0.0128504 | <aucun> | Rez-de-Jardin (Rez-de-Jardin 15545) | 207.8 | 207.8 | 291.4 | 291.4 | 60600 | 617.678 | 291.413 | 2.1196 | 60556.7
Enveloppe fantôme 78703 | Rez-de-Jardin | 78703 | 06 | 02 | Rez-de-Jardin | rectangle | 111.205 | 291.413 | 0 | 291.413 | 178.23 | 291.413 | 358.23 | HAUT Rez-de-Jardin (Rez-de-chaussée 1047) | 0.0128504 | <aucun> | Rez-de-Jardin (Rez-de-Jardin 15545) | 111.2 | 111.2 | 291.4 | 291.4 | 32400 | 330.547 | 291.413 | 1.13429 | 32406.5
Enveloppe fantôme 77961 | Rez-de-Jardin | 77961 | 05 | 02 | Rez-de-Jardin | rectangle | 342.301 | 291.413 | 0 | 291.413 | 89.474 | 291.413 | 269.474 | HAUT Rez-de-Jardin (Rez-de-chaussée 1047) | 0.0128504 | <aucun> | Rez-de-Jardin (Rez-de-Jardin 15545) | 342.3 | 342.3 | 291.4 | 291.4 | 99700 | 1017.46 | 291.413 | 3.49147 | 99751.1
Enveloppe fantôme 77642 | Rez-de-Jardin | 77642 | 04 | 02 | Rez-de-Jardin | rectangle | 421.995 | 291.413 | 0 | 291.413 | 1.27578 | 291.413 | 181.276 | HAUT Rez-de-Jardin (Rez-de-chaussée 1047) | 0.0128504 | <aucun> | Rez-de-Jardin (Rez-de-Jardin 15545) | 422 | 422 | 291.4 | 291.4 | 123000 | 1254.34 | 291.413 | 4.30435 | 122975
Enveloppe fantôme 774241 | Rez-de-chaussée | 774241 | 17 | 03 | Rez-de-chaussée | rectangle | 203.487 | 477.795 | 0.0128504 | 477.795 | 90.4586 | 477.795 | 270.459 | HAUT Rez-de-chaussée (Niveau 1 2343) | 0.0128504 | <aucun> | Rez-de-chaussée (Rez-de-chaussée 1047) | 203.5 | 203.5 | 477.8 | 477.8 | 97200 | 991.698 | 477.795 | 2.07557 | 97225.3
Enveloppe fantôme 45749 | Rez-de-chaussée | 45749 | 02 | 03 | Rez-de-chaussée | rectangle | 136.454 | 477.795 | 0.0128504 | 477.795 | 179.877 | 477.795 | 359.877 | HAUT Rez-de-chaussée (Niveau 1 2343) | 0.0128504 | <aucun> | Rez-de-chaussée (Rez-de-chaussée 1047) | 136.5 | 136.5 | 477.8 | 477.8 | 65200 | 665.01 | 477.795 | 1.39183 | 65197.1
Enveloppe fantôme 45464 | Rez-de-chaussée | 45464 | 01 | 03 | Rez-de-chaussée | rectangle | 189.355 | 477.795 | 0.0128504 | 477.795 | 90.3618 | 477.795 | 270.362 | HAUT Rez-de-chaussée (Niveau 1 2343) | 0.0128504 | <aucun> | Rez-de-chaussée (Rez-de-chaussée 1047) | 189.4 | 189.4 | 477.8 | 477.8 | 90500 | 922.822 | 477.795 | 1.93142 | 90472.8
Enveloppe fantôme 45882 | Rez-de-chaussée | 45882 | 03 | 03 | Rez-de-chaussée | rectangle | 110.432 | 477.795 | 0.0128504 | 477.795 | 91.6845 | 477.795 | 271.685 | HAUT Rez-de-chaussée (Niveau 1 2343) | 0.0128504 | <aucun> | Rez-de-chaussée (Rez-de-chaussée 1047) | 110.4 | 110.4 | 477.8 | 477.8 | 52700 | 538.194 | 477.795 | 1.12641 | 52764.1
Enveloppe fantôme 773669 | Rez-de-chaussée | 773669 | 16 | 03 | Rez-de-chaussée | rectangle | 208.837 | 477.795 | 0.0128504 | 477.795 | 89.1611 | 477.795 | 269.161 | HAUT Rez-de-chaussée (Niveau 1 2343) | 0.0128504 | <aucun> | Rez-de-chaussée (Rez-de-chaussée 1047) | 208.8 | 208.8 | 477.8 | 477.8 | 99800 | 1017.77 | 477.795 | 2.13013 | 99781.2
Enveloppe fantôme 774974 | Niveau 1 | 774974 | 18 | 04 | Niveau 1 | rectangle | 220.199 | 376.102 | 0.0128504 | 376.102 | 90.1931 | 376.102 | 270.193 | HAUT Niveau 1 (Niveau 2 13545) | 9.23706e-12 | <aucun> | Niveau 1 (Niveau 1 2343) | 220.2 | 220.2 | 376.1 | 376.1 | 82800 | 844.736 | 376.102 | 2.24603 | 82817.3
Enveloppe fantôme 775100 | Niveau 1 | 775100 | 19 | 04 | Niveau 1 | rectangle | 203.273 | 376.102 | 0.0128504 | 376.102 | 90.2671 | 376.102 | 270.267 | HAUT Niveau 1 (Niveau 2 13545) | 9.59233e-12 | <aucun> | Niveau 1 (Niveau 1 2343) | 203.3 | 203.3 | 376.1 | 376.1 | 76500 | 779.804 | 376.102 | 2.07338 | 76451.4
Enveloppe fantôme 777347 | Niveau 2 | 777347 | 20 | 05 | Niveau 2 | rectangle | 203.476 | 235 | 0 | 235 | 90.7189 | 235 | 270.719 | HAUT Niveau 2 (Mezzanine 49003) | 1.47438e-11 | <aucun> | Niveau 2 (Niveau 2 13545) | 203.5 | 203.5 | 235 | 235 | 47800 | 487.731 | 235 | 2.07545 | 47816.7
Enveloppe fantôme 176877 | Niveau 2 | 176877 | 07 | 05 | Niveau 2 | rectangle | 314.278 | 235 | 0 | 235 | 90.2953 | 235 | 270.295 | HAUT Niveau 2 (Mezzanine 49003) | 3.73035e-12 | <aucun> | Niveau 2 (Niveau 2 13545) | 314.3 | 314.3 | 235 | 235 | 73900 | 753.325 | 235 | 3.20564 | 73855.4
Enveloppe fantôme 2027984 | Mezzanine | 2027984 | 22 | 06 | Mezzanine | rectangle | 350.744 | 279.702 | 0 | 279.702 | 90.377 | 279.702 | 270.377 | HAUT Mezzanine (Couverture 2134) | 2.73559e-11 | <aucun> | Mezzanine (Mezzanine 49003) | 350.7 | 350.7 | 279.7 | 279.7 | 98100 | 1000.66 | 279.702 | 3.57759 | 98104
Enveloppe fantôme 2042046 | Mezzanine | 2042046 | 24 | 06 | Mezzanine | trapèze | 26.9384 | 279.702 | 0 | 279.702 | 97.6855 | 279.702 | 277.686 | HAUT Mezzanine (Couverture 2134) | 2.73559e-11 | <aucun> | Mezzanine (Mezzanine 49003) | 26.9 | 26.9 | 279.7 | 279.7 | 7500 | 76.8542 | 279.702 | 0.274771 | 7534.73
Enveloppe fantôme 2044191 | Mezzanine | 2044191 | 30 | 06 | Mezzanine | trapèze | 328.225 | 279.702 | 0 | 279.702 | 0.207311 | 279.702 | 180.207 | HAUT Mezzanine (Couverture 2134) | 2.91323e-11 | <aucun> | Mezzanine (Mezzanine 49003) | 328.2 | 328.2 | 279.7 | 279.7 | 91800 | 936.414 | 279.702 | 3.34789 | 91805.3
Enveloppe fantôme 2043862 | Mezzanine | 2043862 | 29 | 06 | Mezzanine | trapèze | 85.6425 | 279.702 | 0 | 279.702 | 89.6572 | 279.702 | 269.657 | HAUT Mezzanine (Couverture 2134) | 2.91323e-11 | <aucun> | Mezzanine (Mezzanine 49003) | 85.6 | 85.6 | 279.7 | 279.7 | 23900 | 244.335 | 279.702 | 0.873554 | 23954.4
Enveloppe fantôme 2045186 | Mezzanine | 2045186 | 32 | 06 | Mezzanine | trapèze | 343.702 | 279.702 | 0 | 279.702 | 0.098214 | 279.702 | 180.098 | HAUT Mezzanine (Couverture 2134) | 2.91323e-11 | <aucun> | Mezzanine (Mezzanine 49003) | 343.7 | 343.7 | 279.7 | 279.7 | 96100 | 980.571 | 279.702 | 3.50576 | 96134.4
Enveloppe fantôme 2044857 | Mezzanine | 2044857 | 31 | 06 | Mezzanine | trapèze | 319.315 | 279.702 | 0 | 279.702 | 89.3927 | 279.702 | 269.393 | HAUT Mezzanine (Couverture 2134) | 2.91323e-11 | <aucun> | Mezzanine (Mezzanine 49003) | 319.3 | 319.3 | 279.7 | 279.7 | 89300 | 910.995 | 279.702 | 3.25701 | 89313.2
Enveloppe fantôme 2043132 | Mezzanine | 2043132 | 26 | 06 | Mezzanine | trapèze | 92.9636 | 279.702 | 0 | 279.702 | 173.675 | 279.702 | 353.675 | HAUT Mezzanine (Couverture 2134) | 2.84217e-11 | <aucun> | Mezzanine (Mezzanine 49003) | 93 | 93 | 279.7 | 279.7 | 26000 | 265.222 | 279.702 | 0.948229 | 26002.1
Enveloppe fantôme 2042855 | Mezzanine | 2042855 | 25 | 06 | Mezzanine | trapèze | 72.4734 | 279.702 | 0 | 279.702 | 178.881 | 279.702 | 358.881 | HAUT Mezzanine (Couverture 2134) | 2.84217e-11 | <aucun> | Mezzanine (Mezzanine 49003) | 72.5 | 72.5 | 279.7 | 279.7 | 20300 | 206.764 | 279.702 | 0.739228 | 20271
Enveloppe fantôme 2043686 | Mezzanine | 2043686 | 28 | 06 | Mezzanine | trapèze | 154.104 | 279.702 | 0 | 279.702 | 0.558822 | 279.702 | 180.559 | HAUT Mezzanine (Couverture 2134) | 2.91323e-11 | <aucun> | Mezzanine (Mezzanine 49003) | 154.1 | 154.1 | 279.7 | 279.7 | 43100 | 439.653 | 279.702 | 1.57186 | 43103.2
Enveloppe fantôme 2043409 | Mezzanine | 2043409 | 27 | 06 | Mezzanine | trapèze | 230.616 | 279.702 | 0 | 279.702 | 90.5588 | 279.702 | 270.559 | HAUT Mezzanine (Couverture 2134) | 2.91323e-11 | <aucun> | Mezzanine (Mezzanine 49003) | 230.6 | 230.6 | 279.7 | 279.7 | 64500 | 657.939 | 279.702 | 2.35228 | 64503.8
Enveloppe fantôme 226769 | Mezzanine | 226769 | 08 | 06 | Mezzanine | trapèze | 147.014 | 100.344 | 0 | 100.344 | 155.426 | 4.35326 | 335.426 | Couverture (Couverture 2134) | 0 | Toit793923 | Mezzanine (Mezzanine 49003) | 147 | 175.5 | 100.3 | 4.4 | 2600 | 78.4989 | 52.3486 | 1.49954 | 7695.97
Enveloppe fantôme 228668 | Mezzanine | 228668 | 14 | 06 | Mezzanine | trapèze | 30.5781 | 253.185 | 0 | 253.185 | 0.406972 | 253.185 | 180.407 | Couverture (Couverture 2134) | 0 | Toit795368 | Mezzanine (Mezzanine 49003) | 30.6 | 30.6 | 253.2 | 253.2 | 7700 | 78.9675 | 253.185 | 0.311897 | 7741.91
Enveloppe fantôme 227429 | Mezzanine | 227429 | 13 | 06 | Mezzanine | trapèze | 72.5399 | 253.185 | 0 | 253.185 | 90.9894 | 245.831 | 270.989 | Couverture (Couverture 2134) | 0 | Toit795368 | Mezzanine (Mezzanine 49003) | 72.5 | 72.9 | 253.2 | 245.8 | 18100 | 184.612 | 249.508 | 0.739907 | 18099.3
Enveloppe fantôme 228670 | Mezzanine | 228670 | 15 | 06 | Mezzanine | trapèze | 49.4142 | 203.214 | 50 | 203.214 | 0.406972 | 203.185 | 180.407 | Couverture (Couverture 2134) | 0 | Toit795368 | Mezzanine (Mezzanine 49003) | 49.4 | 49.4 | 203.2 | 203.2 | 10000 | 102.417 | 203.199 | 0.504025 | 10040.9
Enveloppe fantôme 227036 | Mezzanine | 227036 | 10 | 06 | Mezzanine | rectangle | 110.624 | 279.702 | 0 | 279.702 | 87.3789 | 279.702 | 267.379 | HAUT Mezzanine (Couverture 2134) | 5.68434e-12 | <aucun> | Mezzanine (Mezzanine 49003) | 110.6 | 110.6 | 279.7 | 279.7 | 30900 | 315.606 | 279.702 | 1.12836 | 30941.7
Enveloppe fantôme 226890 | Mezzanine | 226890 | 09 | 06 | Mezzanine | trapèze | 189.171 | 237.963 | 0 | 237.963 | 0.487293 | 501.874 | 180.487 | Couverture (Couverture 2134) | 0 | Toit793923 | Mezzanine (Mezzanine 49003) | 189.2 | 324.7 | 501.9 | 238 | 74600 | 759.06 | 393.389 | 1.92954 | 74417.7
Enveloppe fantôme 227256 | Mezzanine | 227256 | 11 | 06 | Mezzanine | trapèze | 113.329 | 177.314 | 0 | 177.314 | 90.2407 | 229.462 | 270.241 | Couverture (Couverture 2134) | 0 | Toit795368 | Mezzanine (Mezzanine 49003) | 113.3 | 124.7 | 229.5 | 177.3 | 23100 | 235.106 | 203.388 | 1.15595 | 23049.6
Enveloppe fantôme 227377 | Mezzanine | 227377 | 12 | 06 | Mezzanine | trapèze | 363.725 | 196.266 | 0 | 245.831 | 45.5729 | 128.973 | 225.573 | Couverture (Couverture 2134) | 0 | Toit795368 | Mezzanine (Mezzanine 49003) | 363.7 | 382 | 245.8 | 129 | 20500 | 739.427 | 199.307 | 3.71 | 72492.9

# IfcWall: default 100 (3)
Type - Material: <aucun> 10 cm
Description: Enveloppe; Group: ...de stratigraphies = default; ...de matériaux et couleurs = Ivoire clair; ...de matériaux et couleurs - 1 = Ivoire clair; ...de matériaux et couleurs - 2 = Ivoire clair
__RECOGNIZE__ - TPLG: 366; TPLG_OD: 9000; GENERATE: 1
CTLG_EXTERNAL_LINK - 0, DocType: 2; 0, Tag: 0; 0, Crc: 1977773087; 1, DocType: 2; 1, Tag: 100; 1, Crc: 1977773087; 2, DocType: 2; 2, Tag: 200; 2, Crc: 1977773087; 3, DocType: 9; 3, Tag: 0; 3, Crc: 1364580673
IFC_PSET_PolygonOffset - polygonOffsetFactor: 2; polygonOffsetUnits: 2
IFC_Pset_Strat_Detail_Align - ExternalFace: 0
IFC_Pset_Caractéristiques - Stratigraphie: default [100,00]; Épaisseur: 10 cm; Épaisseur VARIABLE: no
IFC_Pset_Caractéristiques_FRUIT - Fruit: no; Taille: 0 cm
IFC_Pset_Géométrie - Forme en Élévation: rectangle
IFC_Pset_Système de Référence Altimétrique_SUPÉRIEUR - sous Niveau: <aucun>
IFC_Pset_Système de Référence Altimétrique_INFÉRIEUR - sous Niveau: <aucun>
IFC_Pset_Matériaux - Face gauche: Ivoire clair; Face droite: Ivoire clair; Face latérale: Ivoire clair
Pset_WallCommon - Reference: default [100,00] (..\VERTICALES\Default\)
BaseQuantities - NominalWidth: 10 cm
Name | In | __RECOGNIZE__, ID = IFC_Pset_Caractéristiques, ID | Alignment | Numérotation | Numéro niveau | Titre niveau | Longueur (cm) = NominalLength (cm) | IFC_Pset_Géométrie, Hauteur (cm) = IFC_Pset_Géométrie_P1 (POINT initial), Hauteur (cm) = IFC_Pset_Géométrie_P2 (POINT final), Hauteur (cm) = NominalHeight (cm) | IFC_Pset_Géométrie, Cote (cm) = IFC_Pset_Géométrie_P1 (POINT initial), Cote (cm) = IFC_Pset_Géométrie_P2 (POINT final), Cote (cm) = IFC_Pset_Système de Référence Altimétrique_INFÉRIEUR, delta (cm) = IFC_Pset_Système de Référence Altimétrique_INFÉRIEUR, delta (P1) (cm) = IFC_Pset_Système de Référence Altimétrique_INFÉRIEUR, delta (P2) (cm) | IFC_Pset_Géométrie_P1 (POINT initial), Angle XY (deg) | IFC_Pset_Géométrie_P2 (POINT final), Angle XY (deg) | IFC_Pset_Système de Référence Altimétrique_SUPÉRIEUR, NIVEAU | IFC_Pset_Système de Référence Altimétrique_SUPÉRIEUR, delta (cm) = IFC_Pset_Système de Référence Altimétrique_SUPÉRIEUR, delta (P1) (cm) = IFC_Pset_Système de Référence Altimétrique_SUPÉRIEUR, delta (P2) (cm) | IFC_Pset_Système de Référence Altimétrique_INFÉRIEUR, NIVEAU | Longueur Pied (cm) = Longueur Tête (cm) | Hauteur Maximale (cm) = Hauteur Minimale (cm) | Surface en Plan (cm2) = Surface Pied (cm2) = Surface Tête (cm2) | Surface de la Paroi (cm2) | Volume (cm3) | GrossVolume (cm3) = NetVolume (cm3) | GrossFootprintArea (cm2) = NetFootprintArea (cm2) | GrossSideArea (cm2) = NetSideArea (cm2)
Enveloppe 3078 | Rez-de-chaussée | 3078 | 0 | 0020 | 03 | Rez-de-chaussée | 241.474 | 477.795 | 0.0128504 | 0.0255063 | 180.026 | HAUT Rez-de-chaussée (Niveau 1 2343) | 0.0128504 | Rez-de-chaussée (Rez-de-chaussée 1047) | 241.5 | 477.8 | 2400 | 115400 | 1150000 | 1153752 | 2414.74 | 115375
Enveloppe 180222 | Niveau 2 | 180222 | 1 | 0471 | 05 | Niveau 2 | 31.5874 | 235 | 1.06581e-12 | 178.213 | 358.213 | HAUT Niveau 2 (Mezzanine 49003) | 0 | Niveau 2 (Niveau 2 13545) | 31.6 | 235 | 300 | 7400 | 70000 | 74230.5 | 315.874 | 7423.05
Enveloppe 180119 | Niveau 2 | 180119 | 0 | 0469 | 05 | Niveau 2 | 30.1209 | 235 | 1.06581e-12 | 179.375 | 359.375 | HAUT Niveau 2 (Mezzanine 49003) | 0 | Niveau 2 (Niveau 2 13545) | 30.1 | 235 | 300 | 7100 | 70000 | 70784.2 | 301.209 | 7078.42

# IfcWall: default 120 (2)
In: Mezzanine
Type - Material: <aucun> 12 cm
Description: Enveloppe; Group: ...de matériaux et couleurs = Chêne; ...de stratigraphies = default; ...de matériaux et couleurs - 1 = Chêne; ...de matériaux et couleurs - 2 = Chêne
__RECOGNIZE__ - TPLG: 366; TPLG_OD: 9000; GENERATE: 1
CTLG_EXTERNAL_LINK - 0, DocType: 2; 0, Tag: 0; 0, Crc: -1156274542; 1, DocType: 2; 1, Tag: 100; 1, Crc: -1156274542; 2, DocType: 2; 2, Tag: 200; 2, Crc: -1156274542; 3, DocType: 9; 3, Tag: 0; 3, Crc: 624124834
IFC_PSET_PolygonOffset - polygonOffsetFactor: 2; polygonOffsetUnits: 2
IFC_Pset_Alignment - Alignment: 0
IFC_Pset_Strat_Detail_Align - ExternalFace: 1
IFC_Pset_Caractéristiques - Numéro niveau: 06; Titre niveau: Mezzanine; Stratigraphie: default [120,00]; Épaisseur: 12 cm; Épaisseur VARIABLE: yes
IFC_Pset_Caractéristiques_FRUIT - Fruit: no; Taille: 0 cm
IFC_Pset_Géométrie - Forme en Élévation: rectangle
IFC_Pset_Système de Référence Altimétrique_SUPÉRIEUR - NIVEAU: HAUT Mezzanine (Couverture 2134); sous Niveau: <aucun>
IFC_Pset_Système de Référence Altimétrique_INFÉRIEUR - NIVEAU: Mezzanine (Mezzanine 49003); sous Niveau: <aucun>
IFC_Pset_Matériaux - Face gauche: Chêne; Face droite: Chêne; Face latérale: Chêne
Pset_WallCommon - Reference: default [120,00] (..\VERTICALES\Default\)
BaseQuantities - NominalWidth: 12 cm
Name | __RECOGNIZE__, ID = IFC_Pset_Caractéristiques, ID | Numérotation | Longueur (cm) = NominalLength (cm) | IFC_Pset_Géométrie, Hauteur (cm) = IFC_Pset_Géométrie_P1 (POINT initial), Hauteur (cm) = IFC_Pset_Géométrie_P2 (POINT final), Hauteur (cm) = NominalHeight (cm) | IFC_Pset_Géométrie, Cote (cm) = IFC_Pset_Géométrie_P1 (POINT initial), Cote (cm) = IFC_Pset_Géométrie_P2 (POINT final), Cote (cm) = IFC_Pset_Système de Référence Altimétrique_INFÉRIEUR, delta (cm) = IFC_Pset_Système de Référence Altimétrique_INFÉRIEUR, delta (P1) (cm) = IFC_Pset_Système de Référence Altimétrique_INFÉRIEUR, delta (P2) (cm) | IFC_Pset_Géométrie_P1 (POINT initial), Angle XY (deg) | IFC_Pset_Géométrie_P2 (POINT final), Angle XY (deg) | IFC_Pset_Système de Référence Altimétrique_SUPÉRIEUR, delta (cm) = IFC_Pset_Système de Référence Altimétrique_SUPÉRIEUR, delta (P1) (cm) = IFC_Pset_Système de Référence Altimétrique_SUPÉRIEUR, delta (P2) (cm) | Longueur Pied (cm) = Longueur Tête (cm) | Hauteur Maximale (cm) = Hauteur Minimale (cm) | Surface en Plan (cm2) = Surface Pied (cm2) = Surface Tête (cm2) | Surface de la Paroi (cm2) | Volume (cm3) | GrossVolume (cm3) = NetVolume (cm3) | GrossFootprintArea (cm2) = NetFootprintArea (cm2) | GrossSideArea (cm2) = NetSideArea (cm2)
Enveloppe 195480 | 195480 | 0484 | 94.7764 | 159.702 | 1.06581e-12 | 89.803 | 269.803 | -120 | 94.8 | 159.7 | 1100 | 15100 | 180000 | 181632 | 1137.32 | 15136
Enveloppe 223005 | 223005 | 0511 | 170.401 | 146.702 | 4.79616e-12 | 1.26484 | 181.265 | -133 | 170.4 | 146.7 | 2000 | 25000 | 300000 | 299979 | 2044.81 | 24998.2

# IfcWall: default 150 (11)
Type - Material: <aucun> 15 cm
Description: Enveloppe
__RECOGNIZE__ - TPLG: 366; TPLG_OD: 9000; GENERATE: 1
CTLG_EXTERNAL_LINK - 0, DocType: 2; 0, Tag: 0; 1, DocType: 2; 1, Tag: 100; 2, DocType: 2; 2, Tag: 200; 3, DocType: 9; 3, Tag: 0; 3, Crc: 1656458995
IFC_PSET_PolygonOffset - polygonOffsetFactor: 2; polygonOffsetUnits: 2
IFC_Pset_Caractéristiques - Stratigraphie: default [150,00]; Épaisseur: 15 cm; Épaisseur VARIABLE: no
IFC_Pset_Caractéristiques_FRUIT - Fruit: no; Taille: 0 cm
IFC_Pset_Système de Référence Altimétrique_INFÉRIEUR - sous Niveau: <aucun>
Pset_WallCommon - Reference: default [150,00] (..\VERTICALES\Default\)
BaseQuantities - NominalWidth: 15 cm
Name | In | __RECOGNIZE__, ID = IFC_Pset_Caractéristiques, ID | 0, Crc = 1, Crc = 2, Crc | Alignment | ExternalFace | Numérotation | Numéro niveau | Titre niveau | Forme en Élévation | Longueur (cm) = NominalLength (cm) | IFC_Pset_Géométrie, Hauteur (cm) = IFC_Pset_Géométrie_P1 (POINT initial), Hauteur (cm) | IFC_Pset_Géométrie, Cote (cm) = IFC_Pset_Géométrie_P1 (POINT initial), Cote (cm) = IFC_Pset_Géométrie_P2 (POINT final), Cote (cm) = IFC_Pset_Système de Référence Altimétrique_INFÉRIEUR, delta (cm) = IFC_Pset_Système de Référence Altimétrique_INFÉRIEUR, delta (P1) (cm) = IFC_Pset_Système de Référence Altimétrique_INFÉRIEUR, delta (P2) (cm) | IFC_Pset_Géométrie_P1 (POINT initial), Angle XY (deg) | IFC_Pset_Géométrie_P2 (POINT final), Hauteur (cm) | IFC_Pset_Géométrie_P2 (POINT final), Angle XY (deg) | IFC_Pset_Système de Référence Altimétrique_SUPÉRIEUR, NIVEAU | IFC_Pset_Système de Référence Altimétrique_SUPÉRIEUR, delta (cm) = IFC_Pset_Système de Référence Altimétrique_SUPÉRIEUR, delta (P1) (cm) = IFC_Pset_Système de Référence Altimétrique_SUPÉRIEUR, delta (P2) (cm) | sous Niveau | IFC_Pset_Système de Référence Altimétrique_INFÉRIEUR, NIVEAU | Longueur Pied (cm) | Longueur Tête (cm) | Hauteur Maximale (cm) | Hauteur Minimale (cm) | Surface en Plan (cm2) = Surface Pied (cm2) | Surface Tête (cm2) | Surface de la Paroi (cm2) | Volume (cm3) | Face gauche = Face droite = Face latérale | GrossVolume (cm3) = NetVolume (cm3) | NominalHeight (cm) | GrossFootprintArea (cm2) = NetFootprintArea (cm2) | GrossSideArea (cm2) = NetSideArea (cm2) | Group
Enveloppe 374872 | Rez-de-chaussée | 374872 | 1977773087 | 0 | 1 | 0642 | 03 | Rez-de-chaussée | rectangle | 49.5654 | 1118.96 | 0.0128504 | 89.9491 | 1118.96 | 269.949 | HAUT Mezzanine (Couverture 2134) | -249.641 | <aucun> | Rez-de-chaussée (Rez-de-chaussée 1047) | 49.6 | 49.6 | 1119 | 1119 | 700 | 700 | 55500 | 830000 | Ivoire clair | 831924 | 1118.96 | 743.481 | 55461.6 | ...de stratigraphies = default; ...de matériaux et couleurs = Ivoire clair; ...de matériaux et couleurs - 1 = Ivoire clair; ...de matériaux et couleurs - 2 = Ivoire clair
Enveloppe 374300 | Rez-de-chaussée | 374300 | 1977773087 | 0 | 1 | 0639 | 03 | Rez-de-chaussée | rectangle | 50.8408 | 1118.96 | 0.0128504 | 89.6732 | 1118.96 | 269.673 | HAUT Mezzanine (Couverture 2134) | -249.641 | <aucun> | Rez-de-chaussée (Rez-de-chaussée 1047) | 50.8 | 50.8 | 1119 | 1119 | 800 | 800 | 56800 | 850000 | Ivoire clair | 853332 | 1118.96 | 762.612 | 56888.8 | ...de stratigraphies = default; ...de matériaux et couleurs = Ivoire clair; ...de matériaux et couleurs - 1 = Ivoire clair; ...de matériaux et couleurs - 2 = Ivoire clair
Enveloppe 375320 | Rez-de-chaussée | 375320 | 1977773087 | 0 | 1 | 0647 | 03 | Rez-de-chaussée | trapèze | 28.6746 | 1109.53 | 0.0128504 | 90.4037 | 1113.34 | 270.404 | Couverture (Couverture 2134) | 0 | Toit782750 | Rez-de-chaussée (Rez-de-chaussée 1047) | 28.7 | 29 | 1113.3 | 1109.5 | 400 | 400 | 31900 | 480000 | Ivoire clair | 478050 | 1111.44 | 430.119 | 31870 | ...de stratigraphies = default; ...de matériaux et couleurs = Ivoire clair; ...de matériaux et couleurs - 1 = Ivoire clair; ...de matériaux et couleurs - 2 = Ivoire clair
Enveloppe 374087 | Rez-de-chaussée | 374087 | 1977773087 | 1 | 1 | 0633 | 03 | Rez-de-chaussée | trapèze | 50.7489 | 1098.4 | 0.0128504 | 179.953 | 1104.69 | 359.953 | Couverture (Couverture 2134) | 0 | Toit783918 | Rez-de-chaussée (Rez-de-chaussée 1047) | 50.7 | 51.1 | 1104.7 | 1098.4 | 800 | 800 | 56000 | 840000 | Ivoire clair | 840745 | 1104.45 | 761.234 | 56049.7 | ...de stratigraphies = default; ...de matériaux et couleurs = Ivoire clair; ...de matériaux et couleurs - 1 = Ivoire clair; ...de matériaux et couleurs - 2 = Ivoire clair
Enveloppe 369602 | Rez-de-chaussée | 369602 | 1977773087 | 0 | 1 | 0606 | 03 | Rez-de-chaussée | trapèze | 49.7974 | 1118.12 | 0.0128504 | 89.0548 | 1104.69 | 269.055 | Couverture (Couverture 2134) | 0 | Toit793924 | Rez-de-chaussée (Rez-de-chaussée 1047) | 49.8 | 51.6 | 1118.1 | 1104.7 | 700 | 900 | 55700 | 840000 | Ivoire clair | 835194 | 1118.12 | 746.96 | 55679.6 | ...de stratigraphies = default; ...de matériaux et couleurs = Ivoire clair; ...de matériaux et couleurs - 1 = Ivoire clair; ...de matériaux et couleurs - 2 = Ivoire clair
Enveloppe 369725 | Rez-de-chaussée | 369725 | 1977773087 | 1 | 1 | 0607 | 03 | Rez-de-chaussée | trapèze | 50.2611 | 1116.63 | 0.0128504 | 179.855 | 1109.45 | 359.855 | Couverture (Couverture 2134) | 0 | Toit793924 | Rez-de-chaussée (Rez-de-chaussée 1047) | 50.3 | 50.8 | 1116.6 | 1109.4 | 800 | 800 | 56200 | 840000 | Ivoire clair | 841694 | 1116.43 | 753.916 | 56112.9 | ...de stratigraphies = default; ...de matériaux et couleurs = Ivoire clair; ...de matériaux et couleurs - 1 = Ivoire clair; ...de matériaux et couleurs - 2 = Ivoire clair
Enveloppe 368022 | Rez-de-chaussée | 368022 | 1977773087 | 1 | 1 | 0597 | 03 | Rez-de-chaussée | trapèze | 52.1625 | 1123.53 | 0.0128504 | 1.03286 | 1103.8 | 181.033 | Couverture (Couverture 2134) | 0 | Toit793924 | Rez-de-chaussée (Rez-de-chaussée 1047) | 52.2 | 55.8 | 1123.5 | 1103.8 | 800 | 900 | 58500 | 880000 | Ivoire clair | 876920 | 1120.76 | 782.437 | 58461.3 | ...de stratigraphies = default; ...de matériaux et couleurs = Ivoire clair; ...de matériaux et couleurs - 1 = Ivoire clair; ...de matériaux et couleurs - 2 = Ivoire clair
Enveloppe 1700678 | Rez-de-chaussée | 1700678 | 1977773087 | 0 | 1 | 1170 | 03 | Rez-de-chaussée | rectangle | 36.7535 | 33.8 | 180 | 90.0993 | 33.8 | 270.099 | HAUT Rez-de-chaussée (Niveau 1 2343) | -263.995 | <aucun> | Rez-de-chaussée (Rez-de-chaussée 1047) | 36.8 | 36.8 | 33.8 | 33.8 | 600 | 600 | 1200 | 20000 | Ivoire clair | 18634 | 33.8 | 551.303 | 1242.27 | ...de stratigraphies = default; ...de matériaux et couleurs = Ivoire clair; ...de matériaux et couleurs - 1 = Ivoire clair; ...de matériaux et couleurs - 2 = Ivoire clair
Enveloppe 460650 | Niveau 2 | 460650 | 1977773087 | 1 | 1 | 0759 | 05 | Niveau 2 | trapèze | 29.1307 | 260.196 | -1.95399e-11 | 44.8795 | 259.997 | 224.88 | Couverture (Couverture 2134) | 0 | Toit782750 | Niveau 2 (Niveau 2 13545) | 29.1 | 29.1 | 260.2 | 260 | 400 | 400 | 7600 | 110000 | Ivoire clair | 113652 | 260.096 | 436.961 | 7576.79 | ...de stratigraphies = default; ...de matériaux et couleurs = Ivoire clair; ...de matériaux et couleurs - 1 = Ivoire clair; ...de matériaux et couleurs - 2 = Ivoire clair
Enveloppe 150037 | Niveau 2 | 150037 | 1977773087 | 0 | 0 | 0321 | 05 | Niveau 2 | rectangle | 110.006 | 235 | 1.42109e-12 | 90.6834 | 235 | 270.683 | HAUT Niveau 2 (Mezzanine 49003) | 0 | <aucun> | Niveau 2 (Niveau 2 13545) | 110 | 110 | 235 | 235 | 1700 | 1700 | 25900 | 390000 | Ivoire clair | 387770 | 235 | 1650.08 | 25851.3 | ...de stratigraphies = default; ...de matériaux et couleurs = Ivoire clair; ...de matériaux et couleurs - 1 = Ivoire clair; ...de matériaux et couleurs - 2 = Ivoire clair
Enveloppe 195655 | Mezzanine | 195655 | -1156274542 | 1 | 1 | 0485 | 06 | Mezzanine | trapèze | 48.209 | 311.909 | 1.06581e-12 | 0.108363 | 233.372 | 180.108 | Couverture (Couverture 2134) | 0 | Toit793923 | Mezzanine (Mezzanine 49003) | 48.2 | 92.1 | 311.9 | 233.4 | 700 | 1400 | 13100 | 200000 | Chêne | 197156 | 272.64 | 723.135 | 13143.7 | ...de matériaux et couleurs = Chêne; ...de stratigraphies = default; ...de matériaux et couleurs - 1 = Chêne; ...de matériaux et couleurs - 2 = Chêne

# IfcWall: default 156, Enveloppe courbe 287179
In: Rez-de-Jardin
Type - Material: <aucun> 15.6 cm
Description: Enveloppe courbe; Group: ...de matériaux et couleurs = Blanc; ...de matériaux et couleurs - 1 = Blanc; ...de matériaux et couleurs - 2 = Blanc; ...de stratigraphies = default
__RECOGNIZE__ - ID: 287179; TPLG: 367; TPLG_OD: 9001; GENERATE: 1
CTLG_EXTERNAL_LINK - 0, DocType: 2; 0, Tag: 0; 0, Crc: -746779066; 1, DocType: 2; 1, Tag: 100; 1, Crc: -746779066; 2, DocType: 2; 2, Tag: 200; 2, Crc: -746779066; 3, DocType: 9; 3, Tag: 0; 3, Crc: 74532560
IFC_PSET_PolygonOffset - polygonOffsetFactor: 2; polygonOffsetUnits: 2
IFC_Pset_Alignment - Alignment: 1
IFC_Pset_Strat_Detail_Align - ExternalFace: 0
IFC_Pset_Caractéristiques - ID: 287179; Numérotation: 40; Numéro niveau: 02; Titre niveau: Rez-de-Jardin; Stratigraphie: default [156,00]; Épaisseur: 15.6 cm; Épaisseur VARIABLE: no
IFC_Pset_Caractéristiques_FRUIT - Fruit: no; Taille: 0 cm
IFC_Pset_Géométrie_P1 (POINT initial) - Hauteur: 111 cm; Cote: 43.7 cm; Angle XY: 0 deg
IFC_Pset_Géométrie_P2 (POINT final) - Hauteur: 106.3 cm; Cote: 43.7 cm; Angle XY: 180 deg
IFC_Pset_Géométrie - Rayon: 0 cm; Point arc: [246,5; -1 294,0] cm; Centre: [245,4; -1 263,2] cm; Angle de la Tangente: 4.46004 deg; Forme en Élévation: trapèze; Longueur: 61.7174 cm; Hauteur: 111 cm; Cote: 43.7 cm
IFC_Pset_Système de Référence Altimétrique_SUPÉRIEUR - NIVEAU: HAUT Rez-de-Jardin (Rez-de-chaussée 1047); delta: -136.7 cm; delta (P1): -136.7 cm; delta (P2): -141.4 cm; sous Niveau: <aucun>
IFC_Pset_Système de Référence Altimétrique_INFÉRIEUR - NIVEAU: Rez-de-Jardin (Rez-de-Jardin 15545); delta: 43.7 cm; delta (P1): 43.7 cm; delta (P2): 43.7 cm; sous Niveau: <aucun>
IFC_Pset_Données Métré - Longueur Pied: 0 cm; Longueur Tête: 4.7 cm; Hauteur Maximale: 111 cm; Hauteur Minimale: 106.3 cm; Surface en Plan: 0 cm2; Surface Pied: 0 cm2; Surface Tête: 100 cm2; Surface de la Paroi: 0 cm2; Volume: 0 cm3
IFC_Pset_Matériaux - Face gauche: Blanc; Face droite: Blanc; Face latérale: Blanc
Pset_WallCommon - Reference: default [156,00] (..\VERTICALES\Default\)
BaseQuantities - GrossVolume: 104607 cm3; NetVolume: 104607 cm3; NominalLength: 61.7174 cm; NominalWidth: 15.6 cm; NominalHeight: 108.65 cm; GrossFootprintArea: 962.792 cm2; NetFootprintArea: 962.792 cm2; GrossSideArea: 6705.6 cm2; NetSideArea: 6705.6 cm2

# IfcWall: default 180, Enveloppe 94350
In: Niveau 1
Type - Material: <aucun> 18 cm
Description: Enveloppe; Group: ...de stratigraphies = default; ...de matériaux et couleurs = Ivoire clair; ...de matériaux et couleurs - 1 = Ivoire clair; ...de matériaux et couleurs - 2 = Ivoire clair
__RECOGNIZE__ - ID: 94350; TPLG: 366; TPLG_OD: 9000; GENERATE: 1
CTLG_EXTERNAL_LINK - 0, DocType: 2; 0, Tag: 0; 0, Crc: 1977773087; 1, DocType: 2; 1, Tag: 100; 1, Crc: 1977773087; 2, DocType: 2; 2, Tag: 200; 2, Crc: 1977773087; 3, DocType: 9; 3, Tag: 0; 3, Crc: -573407016
IFC_PSET_PolygonOffset - polygonOffsetFactor: 2; polygonOffsetUnits: 2
IFC_Pset_Alignment - Alignment: 0
IFC_Pset_Strat_Detail_Align - ExternalFace: 0
IFC_Pset_Caractéristiques - ID: 94350; Numérotation: 0226; Numéro niveau: 04; Titre niveau: Niveau 1; Stratigraphie: default [180,00]; Épaisseur: 18 cm; Épaisseur VARIABLE: yes
IFC_Pset_Caractéristiques_FRUIT - Fruit: no; Taille: 0 cm
IFC_Pset_Géométrie - Forme en Élévation: rectangle; Longueur: 154.153 cm; Hauteur: 376.102 cm; Cote: 0.0128504 cm
IFC_Pset_Géométrie_P1 (POINT initial) - Hauteur: 376.102 cm; Cote: 0.0128504 cm; Angle XY: 0.0141066 deg
IFC_Pset_Géométrie_P2 (POINT final) - Hauteur: 376.102 cm; Cote: 0.0128504 cm; Angle XY: 180.014 deg
IFC_Pset_Système de Référence Altimétrique_SUPÉRIEUR - NIVEAU: HAUT Niveau 1 (Niveau 2 13545); delta: 0 cm; delta (P1): 0 cm; delta (P2): 0 cm; sous Niveau: <aucun>
IFC_Pset_Système de Référence Altimétrique_INFÉRIEUR - NIVEAU: Niveau 1 (Niveau 1 2343); delta: 0.0128504 cm; delta (P1): 0.0128504 cm; delta (P2): 0.0128504 cm; sous Niveau: <aucun>
IFC_Pset_Données Métré - Longueur Pied: 154.2 cm; Longueur Tête: 154.2 cm; Hauteur Maximale: 376.1 cm; Hauteur Minimale: 376.1 cm; Surface en Plan: 2800 cm2; Surface Pied: 2800 cm2; Surface Tête: 2800 cm2; Surface de la Paroi: 58000 cm2; Volume: 1040000 cm3
IFC_Pset_Matériaux - Face gauche: Ivoire clair; Face droite: Ivoire clair; Face latérale: Ivoire clair
Pset_WallCommon - Reference: default [180,00] (..\VERTICALES\Default\)
BaseQuantities - GrossVolume: 1110238 cm3; NetVolume: 1110238 cm3; NominalLength: 154.153 cm; NominalWidth: 19.1496 cm; NominalHeight: 376.102 cm; GrossFootprintArea: 2951.96 cm2; NetFootprintArea: 2951.96 cm2; GrossSideArea: 57977.2 cm2; NetSideArea: 57977.2 cm2

# IfcWall: default 250 (3)
Type - Material: <aucun> 25 cm
Description: Enveloppe; Group: ...de stratigraphies = default; ...de matériaux et couleurs = Ivoire clair; ...de matériaux et couleurs - 1 = Ivoire clair; ...de matériaux et couleurs - 2 = Ivoire clair
__RECOGNIZE__ - TPLG: 366; TPLG_OD: 9000; GENERATE: 1
CTLG_EXTERNAL_LINK - 0, DocType: 2; 0, Tag: 0; 0, Crc: 1977773087; 1, DocType: 2; 1, Tag: 100; 1, Crc: 1977773087; 2, DocType: 2; 2, Tag: 200; 2, Crc: 1977773087; 3, DocType: 9; 3, Tag: 0; 3, Crc: 1541080003
IFC_PSET_PolygonOffset - polygonOffsetFactor: 2; polygonOffsetUnits: 2
IFC_Pset_Caractéristiques - Stratigraphie: default [250,00]; Épaisseur: 25 cm
IFC_Pset_Caractéristiques_FRUIT - Fruit: no; Taille: 0 cm
IFC_Pset_Matériaux - Face gauche: Ivoire clair; Face droite: Ivoire clair; Face latérale: Ivoire clair
Pset_WallCommon - Reference: default [250,00] (..\VERTICALES\Default\)
Name | In | __RECOGNIZE__, ID = IFC_Pset_Caractéristiques, ID | Alignment | ExternalFace | Numérotation | Numéro niveau | Titre niveau | Épaisseur VARIABLE | Forme en Élévation | Longueur (cm) = NominalLength (cm) | IFC_Pset_Géométrie, Hauteur (cm) = IFC_Pset_Géométrie_P1 (POINT initial), Hauteur (cm) | IFC_Pset_Géométrie, Cote (cm) = IFC_Pset_Géométrie_P1 (POINT initial), Cote (cm) = IFC_Pset_Géométrie_P2 (POINT final), Cote (cm) = IFC_Pset_Système de Référence Altimétrique_INFÉRIEUR, delta (cm) = IFC_Pset_Système de Référence Altimétrique_INFÉRIEUR, delta (P1) (cm) = IFC_Pset_Système de Référence Altimétrique_INFÉRIEUR, delta (P2) (cm) | IFC_Pset_Géométrie_P1 (POINT initial), Angle XY (deg) | IFC_Pset_Géométrie_P2 (POINT final), Hauteur (cm) | IFC_Pset_Géométrie_P2 (POINT final), Angle XY (deg) | IFC_Pset_Système de Référence Altimétrique_SUPÉRIEUR, NIVEAU | IFC_Pset_Système de Référence Altimétrique_SUPÉRIEUR, delta (cm) = IFC_Pset_Système de Référence Altimétrique_SUPÉRIEUR, delta (P1) (cm) = IFC_Pset_Système de Référence Altimétrique_SUPÉRIEUR, delta (P2) (cm) | IFC_Pset_Système de Référence Altimétrique_SUPÉRIEUR, sous Niveau | IFC_Pset_Système de Référence Altimétrique_INFÉRIEUR, NIVEAU | IFC_Pset_Système de Référence Altimétrique_INFÉRIEUR, sous Niveau | Longueur Pied (cm) | Longueur Tête (cm) | Hauteur Maximale (cm) | Hauteur Minimale (cm) | Surface en Plan (cm2) = Surface Pied (cm2) | Surface Tête (cm2) | Surface de la Paroi (cm2) | Volume (cm3) | GrossVolume (cm3) | NetVolume (cm3) | NominalWidth (cm) | NominalHeight (cm) | GrossFootprintArea (cm2) = NetFootprintArea (cm2) | GrossSideArea (cm2) | NetSideArea (cm2)
Enveloppe 237492 | Rez-de-Jardin | 237492 | 1 | 1 | 0523 | 02 | Rez-de-Jardin | yes | rectangle | 41.9572 | 1520.2 | -1.94511e-11 | 0.79294 | 1520.2 | 180.793 | Couverture (Couverture 2134) | -139.811 | <aucun> | Rez-de-Jardin (Rez-de-Jardin 15545) | <aucun> | 42 | 42 | 1520.2 | 1520.2 | 1100 | 1100 | 63800 | 1660000 | 1673480 | 1673480 | 26.2369 | 1520.2 | 1100.83 | 63783.4 | 63783.4
Enveloppe 135054 | Rez-de-Jardin | 135054 | 1 | 0 | 0314 | 02 | Rez-de-Jardin | no | rectangle | 161.419 | 441.4 | 0 | 164.52 | 441.4 | 344.52 | HAUT Rez-de-Jardin (Rez-de-chaussée 1047) | 100 | <aucun> | Rez-de-Jardin (Rez-de-Jardin 15545) | extérieur | 161.4 | 161.4 | 441.4 | 441.4 | 4000 | 4000 | 71200 | 1780000 | 1781263 | 816875 | 25 | 441.4 | 4035.48 | 71250.5 | 32675
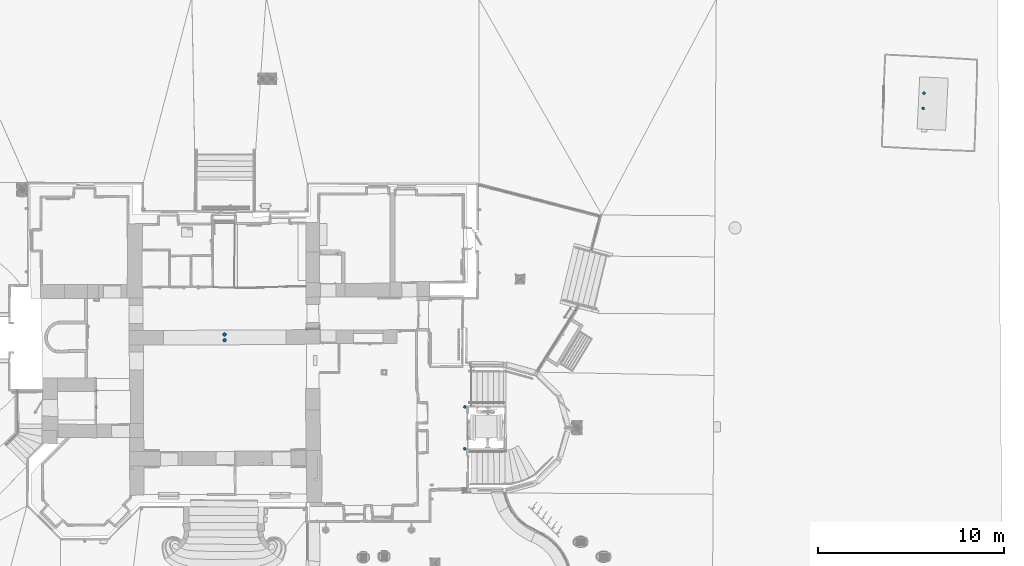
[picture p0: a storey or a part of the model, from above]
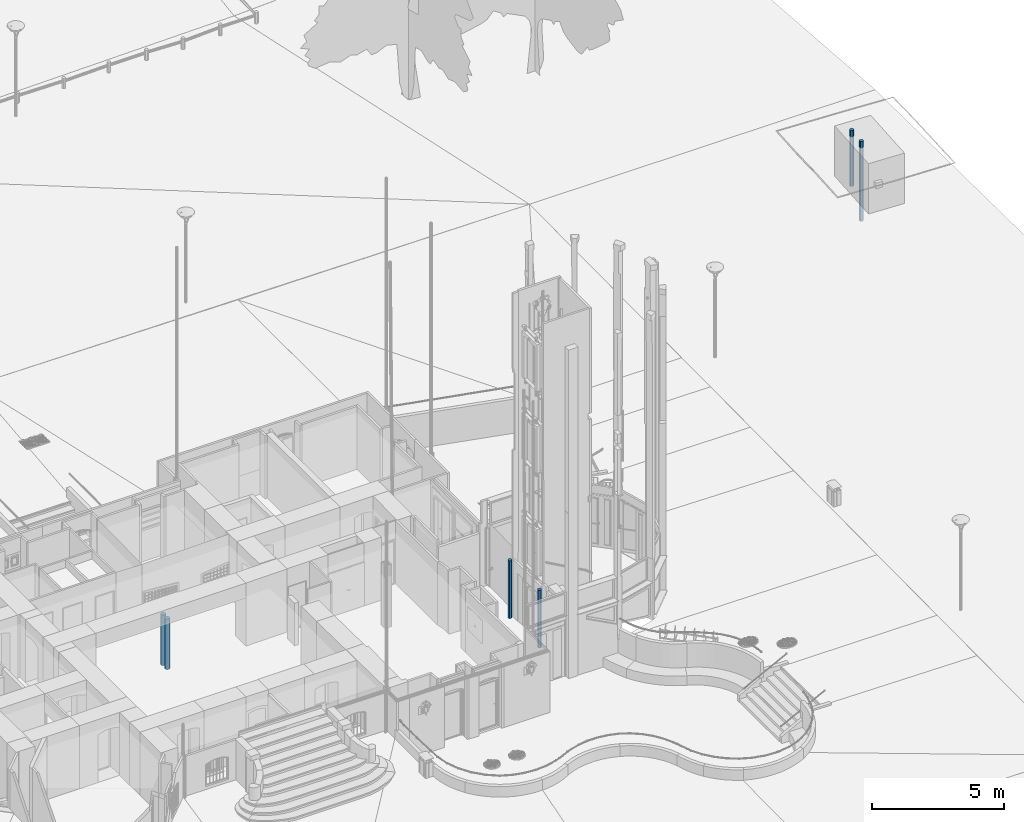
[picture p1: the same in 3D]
Properties of the parts of a building model (IFC2X3), part 19 of 37

# IfcWall: default 250 (3)
Name | In | __RECOGNIZE__, ID = IFC_Pset_Caractéristiques, ID | Alignment | ExternalFace | Numérotation | Numéro niveau | Titre niveau | Épaisseur VARIABLE | Forme en Élévation | Longueur (cm) = NominalLength (cm) | IFC_Pset_Géométrie, Hauteur (cm) = IFC_Pset_Géométrie_P1 (POINT initial), Hauteur (cm) | IFC_Pset_Géométrie, Cote (cm) = IFC_Pset_Géométrie_P1 (POINT initial), Cote (cm) = IFC_Pset_Géométrie_P2 (POINT final), Cote (cm) = IFC_Pset_Système de Référence Altimétrique_INFÉRIEUR, delta (cm) = IFC_Pset_Système de Référence Altimétrique_INFÉRIEUR, delta (P1) (cm) = IFC_Pset_Système de Référence Altimétrique_INFÉRIEUR, delta (P2) (cm) | IFC_Pset_Géométrie_P1 (POINT initial), Angle XY (deg) | IFC_Pset_Géométrie_P2 (POINT final), Hauteur (cm) | IFC_Pset_Géométrie_P2 (POINT final), Angle XY (deg) | IFC_Pset_Système de Référence Altimétrique_SUPÉRIEUR, NIVEAU | IFC_Pset_Système de Référence Altimétrique_SUPÉRIEUR, delta (cm) = IFC_Pset_Système de Référence Altimétrique_SUPÉRIEUR, delta (P1) (cm) = IFC_Pset_Système de Référence Altimétrique_SUPÉRIEUR, delta (P2) (cm) | IFC_Pset_Système de Référence Altimétrique_SUPÉRIEUR, sous Niveau | IFC_Pset_Système de Référence Altimétrique_INFÉRIEUR, NIVEAU | IFC_Pset_Système de Référence Altimétrique_INFÉRIEUR, sous Niveau | Longueur Pied (cm) | Longueur Tête (cm) | Hauteur Maximale (cm) | Hauteur Minimale (cm) | Surface en Plan (cm2) = Surface Pied (cm2) | Surface Tête (cm2) | Surface de la Paroi (cm2) | Volume (cm3) | GrossVolume (cm3) | NetVolume (cm3) | NominalWidth (cm) | NominalHeight (cm) | GrossFootprintArea (cm2) = NetFootprintArea (cm2) | GrossSideArea (cm2) | NetSideArea (cm2)
Enveloppe 727741 | Rez-de-chaussée | 727741 | 0 | 0 | 1063 | 03 | Rez-de-chaussée | no | trapèze | 20.2731 | 1116.84 | 0.0128504 | 89.5447 | 1146.83 | 269.545 | Couverture (Couverture 2134) | 0 | Toit793924 | Rez-de-chaussée (Rez-de-chaussée 1047) | <aucun> | 20.3 | 36.2 | 1146.8 | 1116.8 | 500 | 900 | 23000 | 570000 | 573646 | 573646 | 25 | 1131.84 | 506.827 | 22945.8 | 22945.8

# IfcWall: default 255, Enveloppe 725558
In: Rez-de-chaussée
Type - Material: <aucun> 25.5 cm
Description: Enveloppe; Group: ...de stratigraphies = default; ...de matériaux et couleurs = Ivoire clair; ...de matériaux et couleurs - 1 = Ivoire clair; ...de matériaux et couleurs - 2 = Ivoire clair
__RECOGNIZE__ - ID: 725558; TPLG: 366; TPLG_OD: 9000; GENERATE: 1
CTLG_EXTERNAL_LINK - 0, DocType: 2; 0, Tag: 0; 0, Crc: 1977773087; 1, DocType: 2; 1, Tag: 100; 1, Crc: 1977773087; 2, DocType: 2; 2, Tag: 200; 2, Crc: 1977773087; 3, DocType: 9; 3, Tag: 0; 3, Crc: 2051339170
IFC_PSET_PolygonOffset - polygonOffsetFactor: 2; polygonOffsetUnits: 2
IFC_Pset_Alignment - Alignment: 0
IFC_Pset_Strat_Detail_Align - ExternalFace: 0
IFC_Pset_Caractéristiques - ID: 725558; Numérotation: 1062; Numéro niveau: 03; Titre niveau: Rez-de-chaussée; Stratigraphie: default [255,00]; Épaisseur: 25.5 cm; Épaisseur VARIABLE: no
IFC_Pset_Caractéristiques_FRUIT - Fruit: no; Taille: 0 cm
IFC_Pset_Géométrie - Forme en Élévation: rectangle; Longueur: 20 cm; Hauteur: 1228.79 cm; Cote: 0.0128504 cm
IFC_Pset_Géométrie_P1 (POINT initial) - Hauteur: 1228.79 cm; Cote: 0.0128504 cm; Angle XY: 89.6611 deg
IFC_Pset_Géométrie_P2 (POINT final) - Hauteur: 1228.79 cm; Cote: 0.0128504 cm; Angle XY: 269.661 deg
IFC_Pset_Système de Référence Altimétrique_SUPÉRIEUR - NIVEAU: Couverture (Couverture 2134); delta: -139.811 cm; delta (P1): -139.811 cm; delta (P2): -139.811 cm; sous Niveau: <aucun>
IFC_Pset_Système de Référence Altimétrique_INFÉRIEUR - NIVEAU: Rez-de-chaussée (Rez-de-chaussée 1047); delta: 0.0128504 cm; delta (P1): 0.0128504 cm; delta (P2): 0.0128504 cm; sous Niveau: <aucun>
IFC_Pset_Données Métré - Longueur Pied: 20 cm; Longueur Tête: 20 cm; Hauteur Maximale: 1228.8 cm; Hauteur Minimale: 1228.8 cm; Surface en Plan: 500 cm2; Surface Pied: 500 cm2; Surface Tête: 500 cm2; Surface de la Paroi: 24600 cm2; Volume: 640000 cm3
IFC_Pset_Matériaux - Face gauche: Ivoire clair; Face droite: Ivoire clair; Face latérale: Ivoire clair
Pset_WallCommon - Reference: default [255,00] (..\VERTICALES\Default\)
BaseQuantities - GrossVolume: 626682 cm3; NetVolume: 626682 cm3; NominalLength: 20 cm; NominalWidth: 25.5 cm; NominalHeight: 1228.79 cm; GrossFootprintArea: 510 cm2; NetFootprintArea: 510 cm2; GrossSideArea: 24575.8 cm2; NetSideArea: 24575.8 cm2

# IfcWall: default 260 (7)
Type - Material: <aucun> 26 cm
Description: Enveloppe; Group: ...de stratigraphies = default; ...de matériaux et couleurs = Ivoire clair; ...de matériaux et couleurs - 1 = Ivoire clair; ...de matériaux et couleurs - 2 = Ivoire clair
__RECOGNIZE__ - TPLG: 366; TPLG_OD: 9000; GENERATE: 1
CTLG_EXTERNAL_LINK - 0, DocType: 2; 0, Tag: 0; 0, Crc: 1977773087; 1, DocType: 2; 1, Tag: 100; 1, Crc: 1977773087; 2, DocType: 2; 2, Tag: 200; 2, Crc: 1977773087; 3, DocType: 9; 3, Tag: 0; 3, Crc: 2069987382
IFC_PSET_PolygonOffset - polygonOffsetFactor: 2; polygonOffsetUnits: 2
IFC_Pset_Strat_Detail_Align - ExternalFace: 1
IFC_Pset_Caractéristiques - Stratigraphie: default [260,00]; Épaisseur: 26 cm
IFC_Pset_Caractéristiques_FRUIT - Fruit: no; Taille: 0 cm
IFC_Pset_Géométrie - Forme en Élévation: rectangle
IFC_Pset_Système de Référence Altimétrique_SUPÉRIEUR - sous Niveau: <aucun>
IFC_Pset_Système de Référence Altimétrique_INFÉRIEUR - sous Niveau: <aucun>
IFC_Pset_Matériaux - Face gauche: Ivoire clair; Face droite: Ivoire clair; Face latérale: Ivoire clair
Pset_WallCommon - Reference: default [260,00] (..\VERTICALES\Default\)
Name | In | __RECOGNIZE__, ID = IFC_Pset_Caractéristiques, ID | Alignment | Numérotation | Numéro niveau | Titre niveau | Épaisseur VARIABLE | Longueur (cm) = NominalLength (cm) | IFC_Pset_Géométrie, Hauteur (cm) = IFC_Pset_Géométrie_P1 (POINT initial), Hauteur (cm) = IFC_Pset_Géométrie_P2 (POINT final), Hauteur (cm) = NominalHeight (cm) | IFC_Pset_Géométrie, Cote (cm) = IFC_Pset_Géométrie_P1 (POINT initial), Cote (cm) = IFC_Pset_Géométrie_P2 (POINT final), Cote (cm) = IFC_Pset_Système de Référence Altimétrique_INFÉRIEUR, delta (cm) = IFC_Pset_Système de Référence Altimétrique_INFÉRIEUR, delta (P1) (cm) = IFC_Pset_Système de Référence Altimétrique_INFÉRIEUR, delta (P2) (cm) | IFC_Pset_Géométrie_P1 (POINT initial), Angle XY (deg) | IFC_Pset_Géométrie_P2 (POINT final), Angle XY (deg) | IFC_Pset_Système de Référence Altimétrique_SUPÉRIEUR, NIVEAU | IFC_Pset_Système de Référence Altimétrique_SUPÉRIEUR, delta (cm) = IFC_Pset_Système de Référence Altimétrique_SUPÉRIEUR, delta (P1) (cm) = IFC_Pset_Système de Référence Altimétrique_SUPÉRIEUR, delta (P2) (cm) | IFC_Pset_Système de Référence Altimétrique_INFÉRIEUR, NIVEAU | Longueur Pied (cm) = Longueur Tête (cm) | Hauteur Maximale (cm) = Hauteur Minimale (cm) | Surface en Plan (cm2) = Surface Pied (cm2) = Surface Tête (cm2) | Surface de la Paroi (cm2) | Volume (cm3) | GrossVolume (cm3) | NetVolume (cm3) | NominalWidth (cm) | GrossFootprintArea (cm2) = NetFootprintArea (cm2) | GrossSideArea (cm2) | NetSideArea (cm2)
Enveloppe 451159 | Rez-de-Jardin | 451159 | 0 | 0751 | 02 | Rez-de-Jardin | no | 172.08 | 391.4 | -1.94511e-11 | 179.663 | 359.663 | HAUT Rez-de-Jardin (Rez-de-chaussée 1047) | 100 | Rez-de-Jardin (Rez-de-Jardin 15545) | 172.1 | 391.4 | 4500 | 67400 | 1750000 | 1751161 | 1091914 | 26 | 4474.09 | 67352.3 | 41996.7
Enveloppe 484656 | Rez-de-Jardin | 484656 | 0 | 0833 | 02 | Rez-de-Jardin | no | 20.6694 | 1520.2 | -1.94511e-11 | 179.663 | 359.663 | Couverture (Couverture 2134) | -139.811 | Rez-de-Jardin (Rez-de-Jardin 15545) | 20.7 | 1520.2 | 500 | 31500 | 820000 | 816964 | 816964 | 26 | 537.405 | 31421.7 | 31421.7
Enveloppe 496519 | Rez-de-Jardin | 496519 | 1 | 0837 | 02 | Rez-de-Jardin | yes | 20.3431 | 1520.2 | 3.55271e-13 | 151.017 | 331.017 | Couverture (Couverture 2134) | -139.811 | Rez-de-Jardin (Rez-de-Jardin 15545) | 20.3 | 1520.2 | 500 | 30900 | 830000 | 823417 | 823417 | 26.6257 | 541.65 | 30925.6 | 30925.6
Enveloppe 452747 | Rez-de-chaussée | 452747 | 1 | 0756 | 03 | Rez-de-chaussée | no | 162.004 | 370.795 | 100 | 135.823 | 315.823 | HAUT Rez-de-chaussée (Niveau 1 2343) | -7 | Rez-de-chaussée (Rez-de-chaussée 1047) | 162 | 370.8 | 4200 | 60100 | 1560000 | 1561826 | 167258 | 26 | 4212.1 | 60070.2 | 6433
Enveloppe 532672 | Niveau 1 | 532672 | 0 | 0857 | 04 | Niveau 1 | yes | 180.949 | 383.115 | -7 | 1.21405 | 181.214 | HAUT Niveau 1 (Niveau 2 13545) | 7.4607e-12 | Niveau 1 (Niveau 1 2343) | 180.9 | 383.1 | 4700 | 69300 | 1800000 | 1818630 | 127447 | 26.2337 | 4746.96 | 69324.2 | 4854.34
Enveloppe 532433 | Niveau 1 | 532433 | 1 | 0851 | 04 | Niveau 1 | no | 161.234 | 383.115 | -7 | 15.0092 | 195.009 | HAUT Niveau 1 (Niveau 2 13545) | 7.10543e-12 | Niveau 1 (Niveau 1 2343) | 161.2 | 383.1 | 4200 | 61800 | 1610000 | 1606052 | 99545.4 | 26 | 4192.09 | 61771.2 | 3828.67
Enveloppe 531874 | Niveau 1 | 531874 | 1 | 0850 | 04 | Niveau 1 | no | 173.001 | 383.115 | -7 | 0.194425 | 180.194 | HAUT Niveau 1 (Niveau 2 13545) | 7.10543e-12 | Niveau 1 (Niveau 1 2343) | 173 | 383.1 | 4500 | 66300 | 1720000 | 1723257 | 108522 | 26 | 4498.01 | 66279.1 | 4173.93

# IfcWall: default 270 (2)
In: Rez-de-Jardin
Type - Material: <aucun> 27 cm
Description: Enveloppe; Group: ...de stratigraphies = default; ...de matériaux et couleurs = Ivoire clair; ...de matériaux et couleurs - 1 = Ivoire clair; ...de matériaux et couleurs - 2 = Ivoire clair
__RECOGNIZE__ - TPLG: 366; TPLG_OD: 9000; GENERATE: 1
CTLG_EXTERNAL_LINK - 0, DocType: 2; 0, Tag: 0; 0, Crc: 1977773087; 1, DocType: 2; 1, Tag: 100; 1, Crc: 1977773087; 2, DocType: 2; 2, Tag: 200; 2, Crc: 1977773087; 3, DocType: 9; 3, Tag: 0; 3, Crc: -2078448551
IFC_PSET_PolygonOffset - polygonOffsetFactor: 2; polygonOffsetUnits: 2
IFC_Pset_Alignment - Alignment: 1
IFC_Pset_Strat_Detail_Align - ExternalFace: 1
IFC_Pset_Caractéristiques - Numéro niveau: 02; Titre niveau: Rez-de-Jardin; Stratigraphie: default [270,00]; Épaisseur: 27 cm; Épaisseur VARIABLE: no
IFC_Pset_Caractéristiques_FRUIT - Fruit: no; Taille: 0 cm
IFC_Pset_Géométrie - Forme en Élévation: rectangle
IFC_Pset_Système de Référence Altimétrique_SUPÉRIEUR - NIVEAU: Couverture (Couverture 2134); delta: -139.811 cm; delta (P1): -139.811 cm; delta (P2): -139.811 cm; sous Niveau: <aucun>
IFC_Pset_Système de Référence Altimétrique_INFÉRIEUR - NIVEAU: Rez-de-Jardin (Rez-de-Jardin 15545); sous Niveau: <aucun>
IFC_Pset_Matériaux - Face gauche: Ivoire clair; Face droite: Ivoire clair; Face latérale: Ivoire clair
Pset_WallCommon - Reference: default [270,00] (..\VERTICALES\Default\)
BaseQuantities - NominalWidth: 27 cm
Name | __RECOGNIZE__, ID = IFC_Pset_Caractéristiques, ID | Numérotation | Longueur (cm) = NominalLength (cm) | IFC_Pset_Géométrie, Hauteur (cm) = IFC_Pset_Géométrie_P1 (POINT initial), Hauteur (cm) = IFC_Pset_Géométrie_P2 (POINT final), Hauteur (cm) = Hauteur Maximale (cm) = Hauteur Minimale (cm) = NominalHeight (cm) | IFC_Pset_Géométrie, Cote (cm) = IFC_Pset_Géométrie_P1 (POINT initial), Cote (cm) = IFC_Pset_Géométrie_P2 (POINT final), Cote (cm) = delta (cm) = delta (P1) (cm) = delta (P2) (cm) | IFC_Pset_Géométrie_P1 (POINT initial), Angle XY (deg) | IFC_Pset_Géométrie_P2 (POINT final), Angle XY (deg) | Longueur Pied (cm) = Longueur Tête (cm) | Surface en Plan (cm2) = Surface Pied (cm2) = Surface Tête (cm2) | Surface de la Paroi (cm2) | Volume (cm3) | GrossVolume (cm3) = NetVolume (cm3) | GrossFootprintArea (cm2) = NetFootprintArea (cm2) | GrossSideArea (cm2) = NetSideArea (cm2)
Enveloppe 490224 | 490224 | 0835 | 20.4635 | 1414.2 | 106 | 60.488 | 240.488 | 20.5 | 600 | 29000 | 780000 | 781367 | 552.514 | 28939.5
Enveloppe 499438 | 499438 | 0838 | 20.2499 | 1520.2 | 3.10862e-13 | 175.528 | 355.528 | 20.2 | 500 | 30700 | 830000 | 831165 | 546.747 | 30783.9

# IfcWall: default 280 (2)
Type - Material: <aucun> 28 cm
Description: Enveloppe; Group: ...de stratigraphies = default; ...de matériaux et couleurs = Ivoire clair; ...de matériaux et couleurs - 1 = Ivoire clair; ...de matériaux et couleurs - 2 = Ivoire clair
__RECOGNIZE__ - TPLG: 366; TPLG_OD: 9000; GENERATE: 1
CTLG_EXTERNAL_LINK - 0, DocType: 2; 0, Tag: 0; 0, Crc: 1977773087; 1, DocType: 2; 1, Tag: 100; 1, Crc: 1977773087; 2, DocType: 2; 2, Tag: 200; 2, Crc: 1977773087; 3, DocType: 9; 3, Tag: 0; 3, Crc: -664322277
IFC_PSET_PolygonOffset - polygonOffsetFactor: 2; polygonOffsetUnits: 2
IFC_Pset_Alignment - Alignment: 1
IFC_Pset_Caractéristiques - Stratigraphie: default [280,00]; Épaisseur: 28 cm; Épaisseur VARIABLE: no
IFC_Pset_Caractéristiques_FRUIT - Fruit: no; Taille: 0 cm
IFC_Pset_Géométrie - Forme en Élévation: rectangle
IFC_Pset_Système de Référence Altimétrique_SUPÉRIEUR - sous Niveau: <aucun>
IFC_Pset_Système de Référence Altimétrique_INFÉRIEUR - sous Niveau: <aucun>
IFC_Pset_Matériaux - Face gauche: Ivoire clair; Face droite: Ivoire clair; Face latérale: Ivoire clair
Pset_WallCommon - Reference: default [280,00] (..\VERTICALES\Default\)
BaseQuantities - NominalWidth: 28 cm
Name | In | __RECOGNIZE__, ID = IFC_Pset_Caractéristiques, ID | ExternalFace | Numérotation | Numéro niveau | Titre niveau | Longueur (cm) = NominalLength (cm) | IFC_Pset_Géométrie, Hauteur (cm) = IFC_Pset_Géométrie_P1 (POINT initial), Hauteur (cm) = IFC_Pset_Géométrie_P2 (POINT final), Hauteur (cm) = Hauteur Maximale (cm) = Hauteur Minimale (cm) = NominalHeight (cm) | IFC_Pset_Géométrie, Cote (cm) = IFC_Pset_Géométrie_P1 (POINT initial), Cote (cm) = IFC_Pset_Géométrie_P2 (POINT final), Cote (cm) = IFC_Pset_Système de Référence Altimétrique_INFÉRIEUR, delta (cm) = IFC_Pset_Système de Référence Altimétrique_INFÉRIEUR, delta (P1) (cm) = IFC_Pset_Système de Référence Altimétrique_INFÉRIEUR, delta (P2) (cm) | IFC_Pset_Géométrie_P1 (POINT initial), Angle XY (deg) | IFC_Pset_Géométrie_P2 (POINT final), Angle XY (deg) | IFC_Pset_Système de Référence Altimétrique_SUPÉRIEUR, NIVEAU | IFC_Pset_Système de Référence Altimétrique_SUPÉRIEUR, delta (cm) = IFC_Pset_Système de Référence Altimétrique_SUPÉRIEUR, delta (P1) (cm) = IFC_Pset_Système de Référence Altimétrique_SUPÉRIEUR, delta (P2) (cm) | IFC_Pset_Système de Référence Altimétrique_INFÉRIEUR, NIVEAU | Longueur Pied (cm) = Longueur Tête (cm) | Surface en Plan (cm2) = Surface Pied (cm2) = Surface Tête (cm2) | Surface de la Paroi (cm2) | Volume (cm3) | GrossVolume (cm3) = NetVolume (cm3) | GrossFootprintArea (cm2) = NetFootprintArea (cm2) | GrossSideArea (cm2) = NetSideArea (cm2)
Enveloppe 495942 | Rez-de-Jardin | 495942 | 1 | 0836 | 02 | Rez-de-Jardin | 20.386 | 1414.2 | 106 | 117.999 | 297.999 | Couverture (Couverture 2134) | -139.811 | Rez-de-Jardin (Rez-de-Jardin 15545) | 20.4 | 600 | 28800 | 810000 | 807237 | 570.808 | 28829.9
Enveloppe 172572 | Niveau 2 | 172572 | 0 | 0436 | 05 | Niveau 2 | 105.239 | 39.5 | 208 | 91.0059 | 271.006 | HAUT Niveau 2 (Mezzanine 49003) | 12.5 | Niveau 2 (Niveau 2 13545) | 105.2 | 2900 | 4200 | 120000 | 116394 | 2946.68 | 4156.93

# IfcWall: default 290, Enveloppe 499441
In: Rez-de-Jardin
Type - Material: <aucun> 29 cm
Description: Enveloppe; Group: ...de stratigraphies = default; ...de matériaux et couleurs = Ivoire clair; ...de matériaux et couleurs - 1 = Ivoire clair; ...de matériaux et couleurs - 2 = Ivoire clair
__RECOGNIZE__ - ID: 499441; TPLG: 366; TPLG_OD: 9000; GENERATE: 1
CTLG_EXTERNAL_LINK - 0, DocType: 2; 0, Tag: 0; 0, Crc: 1977773087; 1, DocType: 2; 1, Tag: 100; 1, Crc: 1977773087; 2, DocType: 2; 2, Tag: 200; 2, Crc: 1977773087; 3, DocType: 9; 3, Tag: 0; 3, Crc: 1365445749
IFC_PSET_PolygonOffset - polygonOffsetFactor: 2; polygonOffsetUnits: 2
IFC_Pset_Alignment - Alignment: 0
IFC_Pset_Strat_Detail_Align - ExternalFace: 1
IFC_Pset_Caractéristiques - ID: 499441; Numérotation: 0839; Numéro niveau: 02; Titre niveau: Rez-de-Jardin; Stratigraphie: default [290,00]; Épaisseur: 29 cm; Épaisseur VARIABLE: no
IFC_Pset_Caractéristiques_FRUIT - Fruit: no; Taille: 0 cm
IFC_Pset_Géométrie - Forme en Élévation: rectangle; Longueur: 31.6643 cm; Hauteur: 1414.2 cm; Cote: 106 cm
IFC_Pset_Géométrie_P1 (POINT initial) - Hauteur: 1414.2 cm; Cote: 106 cm; Angle XY: 90.8709 deg
IFC_Pset_Géométrie_P2 (POINT final) - Hauteur: 1414.2 cm; Cote: 106 cm; Angle XY: 270.871 deg
IFC_Pset_Système de Référence Altimétrique_SUPÉRIEUR - NIVEAU: Couverture (Couverture 2134); delta: -139.811 cm; delta (P1): -139.811 cm; delta (P2): -139.811 cm; sous Niveau: <aucun>
IFC_Pset_Système de Référence Altimétrique_INFÉRIEUR - NIVEAU: Rez-de-Jardin (Rez-de-Jardin 15545); delta: 106 cm; delta (P1): 106 cm; delta (P2): 106 cm; sous Niveau: <aucun>
IFC_Pset_Données Métré - Longueur Pied: 31.7 cm; Longueur Tête: 31.7 cm; Hauteur Maximale: 1414.2 cm; Hauteur Minimale: 1414.2 cm; Surface en Plan: 900 cm2; Surface Pied: 900 cm2; Surface Tête: 900 cm2; Surface de la Paroi: 44800 cm2; Volume: 1300000 cm3
IFC_Pset_Matériaux - Face gauche: Ivoire clair; Face droite: Ivoire clair; Face latérale: Ivoire clair
Pset_WallCommon - Reference: default [290,00] (..\VERTICALES\Default\)
BaseQuantities - GrossVolume: 1298612 cm3; NetVolume: 1298612 cm3; NominalLength: 31.6643 cm; NominalWidth: 29 cm; NominalHeight: 1414.2 cm; GrossFootprintArea: 918.265 cm2; NetFootprintArea: 918.265 cm2; GrossSideArea: 44779.7 cm2; NetSideArea: 44779.7 cm2

# IfcWall: default 300, Enveloppe 168295
In: Niveau 2
Type - Material: <aucun> 30 cm
Description: Enveloppe; Group: ...de stratigraphies = default; ...de matériaux et couleurs = Ivoire clair; ...de matériaux et couleurs - 1 = Ivoire clair; ...de matériaux et couleurs - 2 = Ivoire clair
__RECOGNIZE__ - ID: 168295; TPLG: 366; TPLG_OD: 9000; GENERATE: 1
CTLG_EXTERNAL_LINK - 0, DocType: 2; 0, Tag: 0; 0, Crc: 1977773087; 1, DocType: 2; 1, Tag: 100; 1, Crc: 1977773087; 2, DocType: 2; 2, Tag: 200; 2, Crc: 1977773087; 3, DocType: 9; 3, Tag: 0; 3, Crc: -428852228
IFC_PSET_PolygonOffset - polygonOffsetFactor: 2; polygonOffsetUnits: 2
IFC_Pset_Alignment - Alignment: 1
IFC_Pset_Strat_Detail_Align - ExternalFace: 0
IFC_Pset_Caractéristiques - ID: 168295; Numérotation: 0416; Numéro niveau: 05; Titre niveau: Niveau 2; Stratigraphie: default [300,00]; Épaisseur: 30 cm; Épaisseur VARIABLE: no
IFC_Pset_Caractéristiques_FRUIT - Fruit: no; Taille: 0 cm
IFC_Pset_Géométrie - Forme en Élévation: rectangle; Longueur: 112.977 cm; Hauteur: 294.702 cm; Cote: 1.42109e-12 cm
IFC_Pset_Géométrie_P1 (POINT initial) - Hauteur: 294.702 cm; Cote: 1.42109e-12 cm; Angle XY: 91.3079 deg
IFC_Pset_Géométrie_P2 (POINT final) - Hauteur: 294.702 cm; Cote: 1.42109e-12 cm; Angle XY: 271.308 deg
IFC_Pset_Système de Référence Altimétrique_SUPÉRIEUR - NIVEAU: HAUT Mezzanine (Couverture 2134); delta: -220 cm; delta (P1): -220 cm; delta (P2): -220 cm; sous Niveau: <aucun>
IFC_Pset_Système de Référence Altimétrique_INFÉRIEUR - NIVEAU: Niveau 2 (Niveau 2 13545); delta: 1.42109e-12 cm; delta (P1): 1.42109e-12 cm; delta (P2): 1.42109e-12 cm; sous Niveau: <aucun>
IFC_Pset_Données Métré - Longueur Pied: 113 cm; Longueur Tête: 113 cm; Hauteur Maximale: 294.7 cm; Hauteur Minimale: 294.7 cm; Surface en Plan: 3400 cm2; Surface Pied: 3400 cm2; Surface Tête: 3400 cm2; Surface de la Paroi: 33300 cm2; Volume: 1000000 cm3
IFC_Pset_Matériaux - Face gauche: Ivoire clair; Face droite: Ivoire clair; Face latérale: Ivoire clair
Pset_WallCommon - Reference: default [300,00] (..\VERTICALES\Default\)
BaseQuantities - GrossVolume: 998841 cm3; NetVolume: 998841 cm3; NominalLength: 112.977 cm; NominalWidth: 30 cm; NominalHeight: 294.702 cm; GrossFootprintArea: 3389.32 cm2; NetFootprintArea: 3389.32 cm2; GrossSideArea: 33294.7 cm2; NetSideArea: 33294.7 cm2

# IfcWall: default 398 (2)
In: Rez-de-chaussée
Type - Material: <aucun> 39.8 cm
Description: Enveloppe; Group: ...de stratigraphies = default; ...de matériaux et couleurs = Ivoire clair; ...de matériaux et couleurs - 1 = Ivoire clair; ...de matériaux et couleurs - 2 = Ivoire clair
__RECOGNIZE__ - TPLG: 366; TPLG_OD: 9000; GENERATE: 1
CTLG_EXTERNAL_LINK - 0, DocType: 2; 0, Tag: 0; 0, Crc: 1977773087; 1, DocType: 2; 1, Tag: 100; 1, Crc: 1977773087; 2, DocType: 2; 2, Tag: 200; 2, Crc: 1977773087; 3, DocType: 9; 3, Tag: 0; 3, Crc: 1261420166
IFC_PSET_PolygonOffset - polygonOffsetFactor: 2; polygonOffsetUnits: 2
IFC_Pset_Alignment - Alignment: 0
IFC_Pset_Strat_Detail_Align - ExternalFace: 1
IFC_Pset_Caractéristiques - Numéro niveau: 03; Titre niveau: Rez-de-chaussée; Stratigraphie: default [398,00]; Épaisseur: 39.8 cm; Épaisseur VARIABLE: no
IFC_Pset_Caractéristiques_FRUIT - Fruit: no; Taille: 0 cm
IFC_Pset_Géométrie - Forme en Élévation: rectangle
IFC_Pset_Système de Référence Altimétrique_SUPÉRIEUR - NIVEAU: HAUT Rez-de-chaussée (Niveau 1 2343); delta: 0.0128504 cm; delta (P1): 0.0128504 cm; delta (P2): 0.0128504 cm; sous Niveau: <aucun>
IFC_Pset_Système de Référence Altimétrique_INFÉRIEUR - NIVEAU: Rez-de-chaussée (Rez-de-chaussée 1047); sous Niveau: <aucun>
IFC_Pset_Matériaux - Face gauche: Ivoire clair; Face droite: Ivoire clair; Face latérale: Ivoire clair
Pset_WallCommon - Reference: default [398,00] (..\VERTICALES\Default\)
BaseQuantities - NominalWidth: 39.8 cm
Name | __RECOGNIZE__, ID = IFC_Pset_Caractéristiques, ID | Numérotation | Longueur (cm) = NominalLength (cm) | IFC_Pset_Géométrie, Hauteur (cm) = IFC_Pset_Géométrie_P1 (POINT initial), Hauteur (cm) = IFC_Pset_Géométrie_P2 (POINT final), Hauteur (cm) = NominalHeight (cm) | IFC_Pset_Géométrie, Cote (cm) = IFC_Pset_Géométrie_P1 (POINT initial), Cote (cm) = IFC_Pset_Géométrie_P2 (POINT final), Cote (cm) = delta (cm) = delta (P1) (cm) = delta (P2) (cm) | IFC_Pset_Géométrie_P1 (POINT initial), Angle XY (deg) | IFC_Pset_Géométrie_P2 (POINT final), Angle XY (deg) | Longueur Pied (cm) = Longueur Tête (cm) | Hauteur Maximale (cm) = Hauteur Minimale (cm) | Surface en Plan (cm2) = Surface Pied (cm2) = Surface Tête (cm2) | Surface de la Paroi (cm2) | Volume (cm3) | GrossVolume (cm3) | NetVolume (cm3) | GrossFootprintArea (cm2) = NetFootprintArea (cm2) | GrossSideArea (cm2) | NetSideArea (cm2)
Enveloppe 375840 | 375840 | 0652 | 258.186 | 477.795 | 0.0128504 | 179.959 | 359.959 | 258.2 | 477.8 | 10300 | 123400 | 4940000 | 4909724 | 2636400 | 10275.8 | 123360 | 66241.2
Enveloppe 379389 | 379389 | 0666 | 396.128 | 497.808 | -20 | 179.731 | 359.731 | 396.1 | 497.8 | 15800 | 197200 | 7890000 | 7848387 | 2222793 | 15765.9 | 197196 | 55849.1

# IfcWall: default 450, Enveloppe 104962
In: Niveau 1
Type - Material: <aucun> 45 cm
Description: Enveloppe; Group: ...de stratigraphies = default; ...de matériaux et couleurs = Ivoire clair; ...de matériaux et couleurs - 1 = Ivoire clair; ...de matériaux et couleurs - 2 = Ivoire clair
__RECOGNIZE__ - ID: 104962; TPLG: 366; TPLG_OD: 9000; GENERATE: 1
CTLG_EXTERNAL_LINK - 0, DocType: 2; 0, Tag: 0; 0, Crc: 1977773087; 1, DocType: 2; 1, Tag: 100; 1, Crc: 1977773087; 2, DocType: 2; 2, Tag: 200; 2, Crc: 1977773087; 3, DocType: 9; 3, Tag: 0; 3, Crc: -2078066898
IFC_PSET_PolygonOffset - polygonOffsetFactor: 2; polygonOffsetUnits: 2
IFC_Pset_Alignment - Alignment: 0
IFC_Pset_Strat_Detail_Align - ExternalFace: 0
IFC_Pset_Caractéristiques - ID: 104962; Numérotation: 0270; Numéro niveau: 04; Titre niveau: Niveau 1; Stratigraphie: default [450,00]; Épaisseur: 45 cm; Épaisseur VARIABLE: no
IFC_Pset_Caractéristiques_FRUIT - Fruit: no; Taille: 0 cm
IFC_Pset_Géométrie - Forme en Élévation: rectangle; Longueur: 128.882 cm; Hauteur: 145.115 cm; Cote: 231 cm
IFC_Pset_Géométrie_P1 (POINT initial) - Hauteur: 145.115 cm; Cote: 231 cm; Angle XY: 0.303763 deg
IFC_Pset_Géométrie_P2 (POINT final) - Hauteur: 145.115 cm; Cote: 231 cm; Angle XY: 180.304 deg
IFC_Pset_Système de Référence Altimétrique_SUPÉRIEUR - NIVEAU: HAUT Niveau 1 (Niveau 2 13545); delta: 7.10543e-13 cm; delta (P1): 7.10543e-13 cm; delta (P2): 7.10543e-13 cm; sous Niveau: <aucun>
IFC_Pset_Système de Référence Altimétrique_INFÉRIEUR - NIVEAU: Niveau 1 (Niveau 1 2343); delta: 231 cm; delta (P1): 231 cm; delta (P2): 231 cm; sous Niveau: <aucun>
IFC_Pset_Données Métré - Longueur Pied: 128.9 cm; Longueur Tête: 128.9 cm; Hauteur Maximale: 145.1 cm; Hauteur Minimale: 145.1 cm; Surface en Plan: 5800 cm2; Surface Pied: 5800 cm2; Surface Tête: 5800 cm2; Surface de la Paroi: 18700 cm2; Volume: 840000 cm3
IFC_Pset_Matériaux - Face gauche: Ivoire clair; Face droite: Ivoire clair; Face latérale: Ivoire clair
Pset_WallCommon - Reference: default [450,00] (..\VERTICALES\Default\)
BaseQuantities - GrossVolume: 841624 cm3; NetVolume: 841624 cm3; NominalLength: 128.882 cm; NominalWidth: 45 cm; NominalHeight: 145.115 cm; GrossFootprintArea: 5799.7 cm2; NetFootprintArea: 5799.7 cm2; GrossSideArea: 18702.7 cm2; NetSideArea: 18702.7 cm2

# IfcWall: default 540 (2)
In: Niveau 1
Type - Material: <aucun> 54 cm
Description: Enveloppe; Group: ...de stratigraphies = default; ...de matériaux et couleurs = Ivoire clair; ...de matériaux et couleurs - 1 = Ivoire clair; ...de matériaux et couleurs - 2 = Ivoire clair
__RECOGNIZE__ - TPLG: 366; TPLG_OD: 9000; GENERATE: 1
CTLG_EXTERNAL_LINK - 0, DocType: 2; 0, Tag: 0; 0, Crc: 1977773087; 1, DocType: 2; 1, Tag: 100; 1, Crc: 1977773087; 2, DocType: 2; 2, Tag: 200; 2, Crc: 1977773087; 3, DocType: 9; 3, Tag: 0; 3, Crc: -1678105643
IFC_PSET_PolygonOffset - polygonOffsetFactor: 2; polygonOffsetUnits: 2
IFC_Pset_Alignment - Alignment: 1
IFC_Pset_Strat_Detail_Align - ExternalFace: 0
IFC_Pset_Caractéristiques - Numéro niveau: 04; Titre niveau: Niveau 1; Stratigraphie: default [540,00]; Épaisseur: 54 cm; Épaisseur VARIABLE: yes
IFC_Pset_Caractéristiques_FRUIT - Fruit: no; Taille: 0 cm
IFC_Pset_Géométrie - Forme en Élévation: rectangle
IFC_Pset_Système de Référence Altimétrique_SUPÉRIEUR - NIVEAU: HAUT Niveau 1 (Niveau 2 13545); delta: 0 cm; delta (P1): 0 cm; delta (P2): 0 cm; sous Niveau: <aucun>
IFC_Pset_Système de Référence Altimétrique_INFÉRIEUR - NIVEAU: Niveau 1 (Niveau 1 2343); sous Niveau: <aucun>
IFC_Pset_Matériaux - Face gauche: Ivoire clair; Face droite: Ivoire clair; Face latérale: Ivoire clair
Pset_WallCommon - Reference: default [540,00] (..\VERTICALES\Default\)
Name | __RECOGNIZE__, ID = IFC_Pset_Caractéristiques, ID | Numérotation | Longueur (cm) = NominalLength (cm) | IFC_Pset_Géométrie, Hauteur (cm) = IFC_Pset_Géométrie_P1 (POINT initial), Hauteur (cm) = IFC_Pset_Géométrie_P2 (POINT final), Hauteur (cm) = NominalHeight (cm) | IFC_Pset_Géométrie, Cote (cm) = IFC_Pset_Géométrie_P1 (POINT initial), Cote (cm) = IFC_Pset_Géométrie_P2 (POINT final), Cote (cm) = delta (cm) = delta (P1) (cm) = delta (P2) (cm) | IFC_Pset_Géométrie_P1 (POINT initial), Angle XY (deg) | IFC_Pset_Géométrie_P2 (POINT final), Angle XY (deg) | Longueur Pied (cm) = Longueur Tête (cm) | Hauteur Maximale (cm) = Hauteur Minimale (cm) | Surface en Plan (cm2) = Surface Pied (cm2) = Surface Tête (cm2) | Surface de la Paroi (cm2) | Volume (cm3) | GrossVolume (cm3) = NetVolume (cm3) | NominalWidth (cm) | GrossFootprintArea (cm2) = NetFootprintArea (cm2) | GrossSideArea (cm2) = NetSideArea (cm2)
Enveloppe 104994 | 104994 | 0271 | 174.28 | 376.102 | 0.0128504 | 0.064788 | 180.065 | 174.3 | 376.1 | 9500 | 65600 | 3540000 | 3566769 | 54.4154 | 9483.51 | 65547.1
Enveloppe 127392 | 127392 | 0295 | 101.448 | 139.102 | 237.013 | 91.055 | 271.055 | 101.4 | 139.1 | 5700 | 14100 | 790000 | 790584 | 56.0234 | 5683.48 | 14111.7

# IfcWall: default 550, Enveloppe 92931
In: Niveau 1
Type - Material: <aucun> 55 cm
Description: Enveloppe; Group: ...de stratigraphies = default; ...de matériaux et couleurs = Ivoire clair; ...de matériaux et couleurs - 1 = Ivoire clair; ...de matériaux et couleurs - 2 = Ivoire clair
__RECOGNIZE__ - ID: 92931; TPLG: 366; TPLG_OD: 9000; GENERATE: 1
CTLG_EXTERNAL_LINK - 0, DocType: 2; 0, Tag: 0; 0, Crc: 1977773087; 1, DocType: 2; 1, Tag: 100; 1, Crc: 1977773087; 2, DocType: 2; 2, Tag: 200; 2, Crc: 1977773087; 3, DocType: 9; 3, Tag: 0; 3, Crc: 674999326
IFC_PSET_PolygonOffset - polygonOffsetFactor: 2; polygonOffsetUnits: 2
IFC_Pset_Alignment - Alignment: 0
IFC_Pset_Strat_Detail_Align - ExternalFace: 0
IFC_Pset_Caractéristiques - ID: 92931; Numérotation: 0196; Numéro niveau: 04; Titre niveau: Niveau 1; Stratigraphie: default [550,00]; Épaisseur: 55 cm; Épaisseur VARIABLE: no
IFC_Pset_Caractéristiques_FRUIT - Fruit: no; Taille: 0 cm
IFC_Pset_Géométrie - Forme en Élévation: rectangle; Longueur: 27.9948 cm; Hauteur: 376.102 cm; Cote: 0.0128504 cm
IFC_Pset_Géométrie_P1 (POINT initial) - Hauteur: 376.102 cm; Cote: 0.0128504 cm; Angle XY: 90.174 deg
IFC_Pset_Géométrie_P2 (POINT final) - Hauteur: 376.102 cm; Cote: 0.0128504 cm; Angle XY: 270.174 deg
IFC_Pset_Système de Référence Altimétrique_SUPÉRIEUR - NIVEAU: HAUT Niveau 1 (Niveau 2 13545); delta: 0 cm; delta (P1): 0 cm; delta (P2): 0 cm; sous Niveau: <aucun>
IFC_Pset_Système de Référence Altimétrique_INFÉRIEUR - NIVEAU: Niveau 1 (Niveau 1 2343); delta: 0.0128504 cm; delta (P1): 0.0128504 cm; delta (P2): 0.0128504 cm; sous Niveau: <aucun>
IFC_Pset_Données Métré - Longueur Pied: 28 cm; Longueur Tête: 28 cm; Hauteur Maximale: 376.1 cm; Hauteur Minimale: 376.1 cm; Surface en Plan: 1500 cm2; Surface Pied: 1500 cm2; Surface Tête: 1500 cm2; Surface de la Paroi: 10500 cm2; Volume: 580000 cm3
IFC_Pset_Matériaux - Face gauche: Ivoire clair; Face droite: Ivoire clair; Face latérale: Ivoire clair
Pset_WallCommon - Reference: default [550,00] (..\VERTICALES\Default\)
BaseQuantities - GrossVolume: 579091 cm3; NetVolume: 579091 cm3; NominalLength: 27.9948 cm; NominalWidth: 55 cm; NominalHeight: 376.102 cm; GrossFootprintArea: 1539.72 cm2; NetFootprintArea: 1539.72 cm2; GrossSideArea: 10528.9 cm2; NetSideArea: 10528.9 cm2

# IfcWall: default 552.099975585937, Enveloppe 673699
In: Rez-de-chaussée
Type - Material: <aucun> 55.21 cm
Description: Enveloppe; Group: ...de stratigraphies = default; ...de matériaux et couleurs = Ivoire clair; ...de matériaux et couleurs - 1 = Ivoire clair; ...de matériaux et couleurs - 2 = Ivoire clair
__RECOGNIZE__ - ID: 673699; TPLG: 366; TPLG_OD: 9000; GENERATE: 1
CTLG_EXTERNAL_LINK - 0, DocType: 2; 0, Tag: 0; 0, Crc: 1977773087; 1, DocType: 2; 1, Tag: 100; 1, Crc: 1977773087; 2, DocType: 2; 2, Tag: 200; 2, Crc: 1977773087; 3, DocType: 9; 3, Tag: 0; 3, Crc: 1855375277
IFC_PSET_PolygonOffset - polygonOffsetFactor: 2; polygonOffsetUnits: 2
IFC_Pset_Alignment - Alignment: 0
IFC_Pset_Strat_Detail_Align - ExternalFace: 0
IFC_Pset_Caractéristiques - ID: 673699; Numérotation: 1039; Numéro niveau: 03; Titre niveau: Rez-de-chaussée; Stratigraphie: default [552,10]; Épaisseur: 55.21 cm; Épaisseur VARIABLE: yes
IFC_Pset_Caractéristiques_FRUIT - Fruit: no; Taille: 0 cm
IFC_Pset_Géométrie - Forme en Élévation: rectangle; Longueur: 92.5384 cm; Hauteur: 477.795 cm; Cote: 0.0128504 cm
IFC_Pset_Géométrie_P1 (POINT initial) - Hauteur: 477.795 cm; Cote: 0.0128504 cm; Angle XY: 90.9337 deg
IFC_Pset_Géométrie_P2 (POINT final) - Hauteur: 477.795 cm; Cote: 0.0128504 cm; Angle XY: 270.934 deg
IFC_Pset_Système de Référence Altimétrique_SUPÉRIEUR - NIVEAU: HAUT Rez-de-chaussée (Niveau 1 2343); delta: 0.0128504 cm; delta (P1): 0.0128504 cm; delta (P2): 0.0128504 cm; sous Niveau: <aucun>
IFC_Pset_Système de Référence Altimétrique_INFÉRIEUR - NIVEAU: Rez-de-chaussée (Rez-de-chaussée 1047); delta: 0.0128504 cm; delta (P1): 0.0128504 cm; delta (P2): 0.0128504 cm; sous Niveau: <aucun>
IFC_Pset_Données Métré - Longueur Pied: 92.5 cm; Longueur Tête: 92.5 cm; Hauteur Maximale: 477.8 cm; Hauteur Minimale: 477.8 cm; Surface en Plan: 5100 cm2; Surface Pied: 5100 cm2; Surface Tête: 5100 cm2; Surface de la Paroi: 44200 cm2; Volume: 2480000 cm3
IFC_Pset_Matériaux - Face gauche: Ivoire clair; Face droite: Ivoire clair; Face latérale: Ivoire clair
Pset_WallCommon - Reference: default [552,10] (..\VERTICALES\Default\)
BaseQuantities - GrossVolume: 2453022 cm3; NetVolume: 2453022 cm3; NominalLength: 92.5384 cm; NominalWidth: 55.4801 cm; NominalHeight: 477.795 cm; GrossFootprintArea: 5134.04 cm2; NetFootprintArea: 5134.04 cm2; GrossSideArea: 44214.4 cm2; NetSideArea: 44214.4 cm2

# IfcWall: default 556 (2)
In: Rez-de-chaussée
Type - Material: <aucun> 55.6 cm
Description: Enveloppe; Group: ...de stratigraphies = default; ...de matériaux et couleurs = Ivoire clair; ...de matériaux et couleurs - 1 = Ivoire clair; ...de matériaux et couleurs - 2 = Ivoire clair
__RECOGNIZE__ - TPLG: 366; TPLG_OD: 9000; GENERATE: 1
CTLG_EXTERNAL_LINK - 0, DocType: 2; 0, Tag: 0; 0, Crc: 1977773087; 1, DocType: 2; 1, Tag: 100; 1, Crc: 1977773087; 2, DocType: 2; 2, Tag: 200; 2, Crc: 1977773087; 3, DocType: 9; 3, Tag: 0; 3, Crc: -1394158776
IFC_PSET_PolygonOffset - polygonOffsetFactor: 2; polygonOffsetUnits: 2
IFC_Pset_Strat_Detail_Align - ExternalFace: 0
IFC_Pset_Caractéristiques - Numéro niveau: 03; Titre niveau: Rez-de-chaussée; Stratigraphie: default [556,00]; Épaisseur: 55.6 cm; Épaisseur VARIABLE: yes
IFC_Pset_Caractéristiques_FRUIT - Fruit: no; Taille: 0 cm
IFC_Pset_Géométrie - Forme en Élévation: rectangle
IFC_Pset_Système de Référence Altimétrique_SUPÉRIEUR - NIVEAU: HAUT Rez-de-chaussée (Niveau 1 2343); delta: -78.6853 cm; delta (P1): -78.6853 cm; delta (P2): -78.6853 cm; sous Niveau: <aucun>
IFC_Pset_Système de Référence Altimétrique_INFÉRIEUR - NIVEAU: Rez-de-chaussée (Rez-de-chaussée 1047); sous Niveau: <aucun>
IFC_Pset_Matériaux - Face gauche: Ivoire clair; Face droite: Ivoire clair; Face latérale: Ivoire clair
Pset_WallCommon - Reference: default [556,00] (..\VERTICALES\Default\)
Name | __RECOGNIZE__, ID = IFC_Pset_Caractéristiques, ID | Alignment | Numérotation | Longueur (cm) = NominalLength (cm) | IFC_Pset_Géométrie, Hauteur (cm) = IFC_Pset_Géométrie_P1 (POINT initial), Hauteur (cm) = IFC_Pset_Géométrie_P2 (POINT final), Hauteur (cm) = NominalHeight (cm) | IFC_Pset_Géométrie, Cote (cm) = IFC_Pset_Géométrie_P1 (POINT initial), Cote (cm) = IFC_Pset_Géométrie_P2 (POINT final), Cote (cm) = delta (cm) = delta (P1) (cm) = delta (P2) (cm) | IFC_Pset_Géométrie_P1 (POINT initial), Angle XY (deg) | IFC_Pset_Géométrie_P2 (POINT final), Angle XY (deg) | Longueur Pied (cm) = Longueur Tête (cm) | Hauteur Maximale (cm) = Hauteur Minimale (cm) | Surface en Plan (cm2) = Surface Pied (cm2) = Surface Tête (cm2) | Surface de la Paroi (cm2) | Volume (cm3) | GrossVolume (cm3) = NetVolume (cm3) | NominalWidth (cm) | GrossFootprintArea (cm2) = NetFootprintArea (cm2) | GrossSideArea (cm2) = NetSideArea (cm2)
Enveloppe 27047 | 27047 | 0 | 0056 | 129.222 | 134.11 | 265 | 90.2786 | 270.279 | 129.2 | 134.1 | 7200 | 17300 | 970000 | 963547 | 55.6 | 7184.75 | 17330
Enveloppe 2811 | 2811 | 1 | 0012 | 83.8851 | 399.097 | 0.0128504 | 90.4996 | 270.5 | 83.9 | 399.1 | 4700 | 33500 | 1880000 | 1863976 | 55.6771 | 4670.48 | 33478.3

# IfcWall: default 60, Enveloppe 192724
In: Mezzanine
Type - Material: <aucun> 6 cm
Description: Enveloppe; Group: ...de matériaux et couleurs = Chêne; ...de stratigraphies = default; ...de matériaux et couleurs - 1 = Chêne; ...de matériaux et couleurs - 2 = Chêne
__RECOGNIZE__ - ID: 192724; TPLG: 366; TPLG_OD: 9000; GENERATE: 1
CTLG_EXTERNAL_LINK - 0, DocType: 2; 0, Tag: 0; 0, Crc: -1156274542; 1, DocType: 2; 1, Tag: 100; 1, Crc: -1156274542; 2, DocType: 2; 2, Tag: 200; 2, Crc: -1156274542; 3, DocType: 9; 3, Tag: 0; 3, Crc: -662831384
IFC_PSET_PolygonOffset - polygonOffsetFactor: 2; polygonOffsetUnits: 2
IFC_Pset_Alignment - Alignment: 1
IFC_Pset_Strat_Detail_Align - ExternalFace: 1
IFC_Pset_Caractéristiques - ID: 192724; Numérotation: 0474; Numéro niveau: 06; Titre niveau: Mezzanine; Stratigraphie: default [60,00]; Épaisseur: 6 cm; Épaisseur VARIABLE: yes
IFC_Pset_Caractéristiques_FRUIT - Fruit: no; Taille: 0 cm
IFC_Pset_Géométrie - Forme en Élévation: rectangle; Longueur: 76.7442 cm; Hauteur: 132.005 cm; Cote: 48 cm
IFC_Pset_Géométrie_P1 (POINT initial) - Hauteur: 132.005 cm; Cote: 48 cm; Angle XY: 179.573 deg
IFC_Pset_Géométrie_P2 (POINT final) - Hauteur: 132.005 cm; Cote: 48 cm; Angle XY: 359.573 deg
IFC_Pset_Système de Référence Altimétrique_SUPÉRIEUR - NIVEAU: HAUT Mezzanine (Couverture 2134); delta: -99.6977 cm; delta (P1): -99.6977 cm; delta (P2): -99.6977 cm; sous Niveau: <aucun>
IFC_Pset_Système de Référence Altimétrique_INFÉRIEUR - NIVEAU: Mezzanine (Mezzanine 49003); delta: 48 cm; delta (P1): 48 cm; delta (P2): 48 cm; sous Niveau: <aucun>
IFC_Pset_Données Métré - Longueur Pied: 76.7 cm; Longueur Tête: 76.7 cm; Hauteur Maximale: 132 cm; Hauteur Minimale: 132 cm; Surface en Plan: 500 cm2; Surface Pied: 500 cm2; Surface Tête: 500 cm2; Surface de la Paroi: 10100 cm2; Volume: 60000 cm3
IFC_Pset_Matériaux - Face gauche: Chêne; Face droite: Chêne; Face latérale: Chêne
Pset_WallCommon - Reference: default [60,00] (..\VERTICALES\Default\)
BaseQuantities - GrossVolume: 60783.6 cm3; NetVolume: 60783.6 cm3; NominalLength: 76.7442 cm; NominalWidth: 6 cm; NominalHeight: 132.005 cm; GrossFootprintArea: 460.465 cm2; NetFootprintArea: 460.465 cm2; GrossSideArea: 10130.6 cm2; NetSideArea: 10130.6 cm2

# IfcWall: default 630, Enveloppe 103178
In: Niveau 1
Type - Material: <aucun> 63 cm
Description: Enveloppe; Group: ...de stratigraphies = default; ...de matériaux et couleurs = Ivoire clair; ...de matériaux et couleurs - 1 = Ivoire clair; ...de matériaux et couleurs - 2 = Ivoire clair
__RECOGNIZE__ - ID: 103178; TPLG: 366; TPLG_OD: 9000; GENERATE: 1
CTLG_EXTERNAL_LINK - 0, DocType: 2; 0, Tag: 0; 0, Crc: 1977773087; 1, DocType: 2; 1, Tag: 100; 1, Crc: 1977773087; 2, DocType: 2; 2, Tag: 200; 2, Crc: 1977773087; 3, DocType: 9; 3, Tag: 0; 3, Crc: -1241460511
IFC_PSET_PolygonOffset - polygonOffsetFactor: 2; polygonOffsetUnits: 2
IFC_Pset_Alignment - Alignment: 1
IFC_Pset_Strat_Detail_Align - ExternalFace: 1
IFC_Pset_Caractéristiques - ID: 103178; Numérotation: 0252; Numéro niveau: 04; Titre niveau: Niveau 1; Stratigraphie: default [630,00]; Épaisseur: 63 cm; Épaisseur VARIABLE: yes
IFC_Pset_Caractéristiques_FRUIT - Fruit: no; Taille: 0 cm
IFC_Pset_Géométrie - Forme en Élévation: rectangle; Longueur: 30.8932 cm; Hauteur: 376.102 cm; Cote: 0.0128504 cm
IFC_Pset_Géométrie_P1 (POINT initial) - Hauteur: 376.102 cm; Cote: 0.0128504 cm; Angle XY: 90.174 deg
IFC_Pset_Géométrie_P2 (POINT final) - Hauteur: 376.102 cm; Cote: 0.0128504 cm; Angle XY: 270.174 deg
IFC_Pset_Système de Référence Altimétrique_SUPÉRIEUR - NIVEAU: HAUT Niveau 1 (Niveau 2 13545); delta: 0 cm; delta (P1): 0 cm; delta (P2): 0 cm; sous Niveau: <aucun>
IFC_Pset_Système de Référence Altimétrique_INFÉRIEUR - NIVEAU: Niveau 1 (Niveau 1 2343); delta: 0.0128504 cm; delta (P1): 0.0128504 cm; delta (P2): 0.0128504 cm; sous Niveau: <aucun>
IFC_Pset_Données Métré - Longueur Pied: 30.9 cm; Longueur Tête: 30.9 cm; Hauteur Maximale: 376.1 cm; Hauteur Minimale: 376.1 cm; Surface en Plan: 1900 cm2; Surface Pied: 1900 cm2; Surface Tête: 1900 cm2; Surface de la Paroi: 11600 cm2; Volume: 730000 cm3
IFC_Pset_Matériaux - Face gauche: Ivoire clair; Face droite: Ivoire clair; Face latérale: Ivoire clair
Pset_WallCommon - Reference: default [630,00] (..\VERTICALES\Default\)
BaseQuantities - GrossVolume: 745682 cm3; NetVolume: 745682 cm3; NominalLength: 30.8932 cm; NominalWidth: 64.1777 cm; NominalHeight: 376.102 cm; GrossFootprintArea: 1982.66 cm2; NetFootprintArea: 1982.66 cm2; GrossSideArea: 11619 cm2; NetSideArea: 11619 cm2

# IfcWall: default 740, Enveloppe 71290
In: Rez-de-Jardin
Type - Material: <aucun> 74 cm
Description: Enveloppe; Group: ...de stratigraphies = default; ...de matériaux et couleurs = 18 Travertin romain; ...de matériaux et couleurs - 1 = 18 Travertin romain; ...de matériaux et couleurs - 2 = 18 Travertin romain
__RECOGNIZE__ - ID: 71290; TPLG: 366; TPLG_OD: 9000; GENERATE: 1
CTLG_EXTERNAL_LINK - 0, DocType: 2; 0, Tag: 0; 0, Crc: 1552655706; 1, DocType: 2; 1, Tag: 100; 1, Crc: 1552655706; 2, DocType: 2; 2, Tag: 200; 2, Crc: 1552655706; 3, DocType: 9; 3, Tag: 0; 3, Crc: 1957607397
IFC_PSET_PolygonOffset - polygonOffsetFactor: 2; polygonOffsetUnits: 2
IFC_Pset_Alignment - Alignment: 0
IFC_Pset_Strat_Detail_Align - ExternalFace: 1
IFC_Pset_Caractéristiques - ID: 71290; Numérotation: 0148; Numéro niveau: 02; Titre niveau: Rez-de-Jardin; Stratigraphie: default [740,00]; Épaisseur: 74 cm; Épaisseur VARIABLE: yes
IFC_Pset_Caractéristiques_FRUIT - Fruit: no; Taille: 0 cm
IFC_Pset_Géométrie - Forme en Élévation: rectangle; Longueur: 70.5582 cm; Hauteur: 291.413 cm; Cote: -1.94511e-11 cm
IFC_Pset_Géométrie_P1 (POINT initial) - Hauteur: 291.413 cm; Cote: -1.94511e-11 cm; Angle XY: 89.4074 deg
IFC_Pset_Géométrie_P2 (POINT final) - Hauteur: 291.413 cm; Cote: -1.94511e-11 cm; Angle XY: 269.407 deg
IFC_Pset_Système de Référence Altimétrique_SUPÉRIEUR - NIVEAU: HAUT Rez-de-Jardin (Rez-de-chaussée 1047); delta: 0.0128504 cm; delta (P1): 0.0128504 cm; delta (P2): 0.0128504 cm; sous Niveau: <aucun>
IFC_Pset_Système de Référence Altimétrique_INFÉRIEUR - NIVEAU: Rez-de-Jardin (Rez-de-Jardin 15545); delta: -1.94511e-11 cm; delta (P1): -1.94511e-11 cm; delta (P2): -1.94511e-11 cm; sous Niveau: <aucun>
IFC_Pset_Données Métré - Longueur Pied: 70.6 cm; Longueur Tête: 70.6 cm; Hauteur Maximale: 291.4 cm; Hauteur Minimale: 291.4 cm; Surface en Plan: 5200 cm2; Surface Pied: 5200 cm2; Surface Tête: 5200 cm2; Surface de la Paroi: 20600 cm2; Volume: 1520000 cm3
IFC_Pset_Matériaux - Face gauche: 18 Travertin romain; Face droite: 18 Travertin romain; Face latérale: 18 Travertin romain
Pset_WallCommon - Reference: default [740,00] (..\VERTICALES\Default\)
BaseQuantities - GrossVolume: 1659876 cm3; NetVolume: 1659876 cm3; NominalLength: 70.5582 cm; NominalWidth: 80.727 cm; NominalHeight: 291.413 cm; GrossFootprintArea: 5695.95 cm2; NetFootprintArea: 5695.95 cm2; GrossSideArea: 20561.6 cm2; NetSideArea: 20561.6 cm2

# IfcWall: default 77, Enveloppe courbe 170058
In: Niveau 2
Type - Material: <aucun> 7.7 cm
Description: Enveloppe courbe; Group: ...de matériaux et couleurs = Blanc; ...de matériaux et couleurs - 1 = Blanc; ...de matériaux et couleurs - 2 = Blanc; ...de stratigraphies = default
__RECOGNIZE__ - ID: 170058; TPLG: 367; TPLG_OD: 9001; GENERATE: 1
CTLG_EXTERNAL_LINK - 0, DocType: 2; 0, Tag: 0; 0, Crc: -746779066; 1, DocType: 2; 1, Tag: 100; 1, Crc: -746779066; 2, DocType: 2; 2, Tag: 200; 2, Crc: -746779066; 3, DocType: 9; 3, Tag: 0; 3, Crc: -193091668
IFC_PSET_PolygonOffset - polygonOffsetFactor: 2; polygonOffsetUnits: 2
IFC_Pset_Alignment - Alignment: 1
IFC_Pset_Strat_Detail_Align - ExternalFace: 0
IFC_Pset_Caractéristiques - ID: 170058; Numérotation: 11; Numéro niveau: 05; Titre niveau: Niveau 2; Stratigraphie: default [77,00]; Épaisseur: 7.7 cm; Épaisseur VARIABLE: no
IFC_Pset_Caractéristiques_FRUIT - Fruit: no; Taille: 0 cm
IFC_Pset_Géométrie_P1 (POINT initial) - Hauteur: 303.105 cm; Cote: 0 cm; Angle XY: 19.4313 deg
IFC_Pset_Géométrie_P2 (POINT final) - Hauteur: 314.914 cm; Cote: 0 cm; Angle XY: 199.431 deg
IFC_Pset_Géométrie - Rayon: 104.492 cm; Point arc: [-722,4; -211,3] cm; Centre: [-692,1; -115,3] cm; Angle de la Tangente: 7.51086 deg; Forme en Élévation: trapèze; Longueur: 35.4373 cm; Hauteur: 303.105 cm; Cote: 0 cm
IFC_Pset_Système de Référence Altimétrique_SUPÉRIEUR - NIVEAU: HAUT Mezzanine (Couverture 2134); delta: 0 cm; delta (P1): 0 cm; delta (P2): 0 cm; sous Niveau: <aucun>
IFC_Pset_Système de Référence Altimétrique_INFÉRIEUR - NIVEAU: Niveau 2 (Niveau 2 13545); delta: 0 cm; delta (P1): 0 cm; delta (P2): 0 cm; sous Niveau: <aucun>
IFC_Pset_Données Métré - Longueur Pied: 35.4 cm; Longueur Tête: 37.3 cm; Hauteur Maximale: 314.9 cm; Hauteur Minimale: 303.1 cm; Surface en Plan: 200 cm2; Surface Pied: 300 cm2; Surface Tête: 300 cm2; Surface de la Paroi: 10900 cm2; Volume: 90000 cm3
IFC_Pset_Matériaux - Face gauche: Blanc; Face droite: Blanc; Face latérale: Blanc
Pset_WallCommon - Reference: default [77,00] (..\VERTICALES\Default\)
BaseQuantities - GrossVolume: 83973 cm3; NetVolume: 83973 cm3; NominalLength: 35.4373 cm; NominalWidth: 7.66844 cm; NominalHeight: 309.009 cm; GrossFootprintArea: 271.749 cm2; NetFootprintArea: 271.749 cm2; GrossSideArea: 10950.5 cm2; NetSideArea: 10950.5 cm2

# IfcWall: default 80, Enveloppe 170242
In: Niveau 2
Type - Material: <aucun> 8 cm
Description: Enveloppe; Group: ...de stratigraphies = default; ...de matériaux et couleurs = Ivoire clair; ...de matériaux et couleurs - 1 = Ivoire clair; ...de matériaux et couleurs - 2 = Ivoire clair
__RECOGNIZE__ - ID: 170242; TPLG: 366; TPLG_OD: 9000; GENERATE: 1
CTLG_EXTERNAL_LINK - 0, DocType: 2; 0, Tag: 0; 0, Crc: 1977773087; 1, DocType: 2; 1, Tag: 100; 1, Crc: 1977773087; 2, DocType: 2; 2, Tag: 200; 2, Crc: 1977773087; 3, DocType: 9; 3, Tag: 0; 3, Crc: -1554559915
IFC_PSET_PolygonOffset - polygonOffsetFactor: 2; polygonOffsetUnits: 2
IFC_Pset_Alignment - Alignment: 1
IFC_Pset_Strat_Detail_Align - ExternalFace: 0
IFC_Pset_Caractéristiques - ID: 170242; Numérotation: 0419; Numéro niveau: 05; Titre niveau: Niveau 2; Stratigraphie: default [80,00]; Épaisseur: 8 cm; Épaisseur VARIABLE: no
IFC_Pset_Caractéristiques_FRUIT - Fruit: no; Taille: 0 cm
IFC_Pset_Géométrie - Forme en Élévation: trapèze; Longueur: 34.4507 cm; Hauteur: 315.632 cm; Cote: 1.42109e-12 cm
IFC_Pset_Géométrie_P1 (POINT initial) - Hauteur: 315.632 cm; Cote: 1.42109e-12 cm; Angle XY: 90.1529 deg
IFC_Pset_Géométrie_P2 (POINT final) - Hauteur: 348.004 cm; Cote: 1.42109e-12 cm; Angle XY: 270.153 deg
IFC_Pset_Système de Référence Altimétrique_SUPÉRIEUR - NIVEAU: Couverture (Couverture 2134); delta: 0 cm; delta (P1): 0 cm; delta (P2): 0 cm; sous Niveau: Toit795367
IFC_Pset_Système de Référence Altimétrique_INFÉRIEUR - NIVEAU: Niveau 2 (Niveau 2 13545); delta: 1.42109e-12 cm; delta (P1): 1.42109e-12 cm; delta (P2): 1.42109e-12 cm; sous Niveau: <aucun>
IFC_Pset_Données Métré - Longueur Pied: 34.5 cm; Longueur Tête: 47.3 cm; Hauteur Maximale: 348 cm; Hauteur Minimale: 315.6 cm; Surface en Plan: 300 cm2; Surface Pied: 300 cm2; Surface Tête: 400 cm2; Surface de la Paroi: 11400 cm2; Volume: 90000 cm3
IFC_Pset_Matériaux - Face gauche: Ivoire clair; Face droite: Ivoire clair; Face latérale: Ivoire clair
Pset_WallCommon - Reference: default [80,00] (..\VERTICALES\Default\)
BaseQuantities - GrossVolume: 91450.8 cm3; NetVolume: 91450.8 cm3; NominalLength: 34.4507 cm; NominalWidth: 8 cm; NominalHeight: 331.818 cm; GrossFootprintArea: 275.606 cm2; NetFootprintArea: 275.606 cm2; GrossSideArea: 11431.3 cm2; NetSideArea: 11431.3 cm2

# IfcWall: default 90 (16)
Type - Material: <aucun> 9 cm
Description: Enveloppe
__RECOGNIZE__ - TPLG: 366; TPLG_OD: 9000; GENERATE: 1
CTLG_EXTERNAL_LINK - 0, DocType: 2; 0, Tag: 0; 1, DocType: 2; 1, Tag: 100; 2, DocType: 2; 2, Tag: 200; 3, DocType: 9; 3, Tag: 0; 3, Crc: 923632929
IFC_PSET_PolygonOffset - polygonOffsetFactor: 2; polygonOffsetUnits: 2
IFC_Pset_Caractéristiques - Stratigraphie: default [90,00]; Épaisseur: 9 cm
IFC_Pset_Caractéristiques_FRUIT - Fruit: no; Taille: 0 cm
Pset_WallCommon - Reference: default [90,00] (..\VERTICALES\Default\)
BaseQuantities - NominalWidth: 9 cm
Name | In | __RECOGNIZE__, ID = IFC_Pset_Caractéristiques, ID | 0, Crc = 1, Crc = 2, Crc | Alignment | ExternalFace | Numérotation | Numéro niveau | Titre niveau | Épaisseur VARIABLE | Forme en Élévation | Longueur (cm) = NominalLength (cm) | IFC_Pset_Géométrie, Hauteur (cm) = IFC_Pset_Géométrie_P1 (POINT initial), Hauteur (cm) | IFC_Pset_Géométrie, Cote (cm) = IFC_Pset_Géométrie_P1 (POINT initial), Cote (cm) = IFC_Pset_Géométrie_P2 (POINT final), Cote (cm) = IFC_Pset_Système de Référence Altimétrique_INFÉRIEUR, delta (cm) = IFC_Pset_Système de Référence Altimétrique_INFÉRIEUR, delta (P1) (cm) = IFC_Pset_Système de Référence Altimétrique_INFÉRIEUR, delta (P2) (cm) | IFC_Pset_Géométrie_P1 (POINT initial), Angle XY (deg) | IFC_Pset_Géométrie_P2 (POINT final), Hauteur (cm) | IFC_Pset_Géométrie_P2 (POINT final), Angle XY (deg) | IFC_Pset_Système de Référence Altimétrique_SUPÉRIEUR, NIVEAU | IFC_Pset_Système de Référence Altimétrique_SUPÉRIEUR, delta (cm) = IFC_Pset_Système de Référence Altimétrique_SUPÉRIEUR, delta (P1) (cm) = IFC_Pset_Système de Référence Altimétrique_SUPÉRIEUR, delta (P2) (cm) | IFC_Pset_Système de Référence Altimétrique_SUPÉRIEUR, sous Niveau | IFC_Pset_Système de Référence Altimétrique_INFÉRIEUR, NIVEAU | IFC_Pset_Système de Référence Altimétrique_INFÉRIEUR, sous Niveau | Longueur Pied (cm) | Longueur Tête (cm) | Hauteur Maximale (cm) | Hauteur Minimale (cm) | Surface en Plan (cm2) = Surface Pied (cm2) = Surface Tête (cm2) | Surface de la Paroi (cm2) | Volume (cm3) | Face gauche = Face droite = Face latérale | GrossVolume (cm3) | NetVolume (cm3) | NominalHeight (cm) | GrossFootprintArea (cm2) = NetFootprintArea (cm2) | GrossSideArea (cm2) | NetSideArea (cm2) | Group
Enveloppe 567350 | Rez-de-Jardin | 567350 | 1977773087 | 0 | 1 | 0879 | 02 | Rez-de-Jardin | no | rectangle | 186.456 | 1500.02 | 7.4607e-12 | 0.135642 | 1500.02 | 180.136 | HAUT Mezzanine (Couverture 2134) | -159.994 | <aucun> | Rez-de-Jardin (Rez-de-Jardin 15545) | <aucun> | 186.5 | 186.5 | 1500 | 1500 | 1700 | 279800 | 2520000 | Ivoire clair | 2517194 | 2517194 | 1500.02 | 1678.11 | 279688 | 279688 | ...de stratigraphies = default; ...de matériaux et couleurs = Ivoire clair; ...de matériaux et couleurs - 1 = Ivoire clair; ...de matériaux et couleurs - 2 = Ivoire clair
Enveloppe 567826 | Rez-de-Jardin | 567826 | 1977773087 | 1 | 1 | 0880 | 02 | Rez-de-Jardin | no | rectangle | 231.112 | 1495.01 | 7.4607e-12 | 90.0947 | 1495.01 | 270.095 | HAUT Mezzanine (Couverture 2134) | -165 | <aucun> | Rez-de-Jardin (Rez-de-Jardin 15545) | <aucun> | 231.1 | 231.1 | 1495 | 1495 | 2100 | 345500 | 3110000 | Ivoire clair | 3109637 | 2956430 | 1495.01 | 2080.01 | 345515 | 328492 | ...de stratigraphies = default; ...de matériaux et couleurs = Ivoire clair; ...de matériaux et couleurs - 1 = Ivoire clair; ...de matériaux et couleurs - 2 = Ivoire clair
Enveloppe 773670 | Rez-de-Jardin | 773670 | 1977773087 | 0 | 1 | 1111 | 02 | Rez-de-Jardin | no | rectangle | 24.3258 | 1495.01 | 7.4607e-12 | 0.135642 | 1495.01 | 180.136 | HAUT Mezzanine (Couverture 2134) | -165 | <aucun> | Rez-de-Jardin (Rez-de-Jardin 15545) | <aucun> | 24.3 | 24.3 | 1495 | 1495 | 200 | 36300 | 330000 | Ivoire clair | 327306 | 327306 | 1495.01 | 218.932 | 36367.3 | 36367.3 | ...de stratigraphies = default; ...de matériaux et couleurs = Ivoire clair; ...de matériaux et couleurs - 1 = Ivoire clair; ...de matériaux et couleurs - 2 = Ivoire clair
Enveloppe 594550 | Rez-de-Jardin | 594550 | 1977773087 | 0 | 1 | 0936 | 02 | Rez-de-Jardin | yes | rectangle | 316.542 | 291.413 | -1.94511e-11 | 90.2125 | 291.413 | 270.213 | HAUT Rez-de-Jardin (Rez-de-chaussée 1047) | 0.0128504 | <aucun> | Rez-de-Jardin (Rez-de-Jardin 15545) | <aucun> | 316.5 | 316.5 | 291.4 | 291.4 | 2800 | 92200 | 830000 | Ivoire clair | 830201 | 830201 | 291.413 | 2848.88 | 92244.6 | 92244.6 | ...de stratigraphies = default; ...de matériaux et couleurs = Ivoire clair; ...de matériaux et couleurs - 1 = Ivoire clair; ...de matériaux et couleurs - 2 = Ivoire clair
Enveloppe 352607 | Rez-de-Jardin | 352607 | 1552655706 | 0 | 1 | 0569 | 02 | Rez-de-Jardin | no | rectangle | 67.2946 | 281.4 | -1.94511e-11 | 88.9442 | 281.4 | 268.944 | HAUT Rez-de-Jardin (Rez-de-chaussée 1047) | -10 | <aucun> | Rez-de-Jardin (Rez-de-Jardin 15545) | <aucun> | 67.3 | 67.3 | 281.4 | 281.4 | 600 | 18900 | 170000 | 18 Travertin romain | 170431 | 170431 | 281.4 | 605.652 | 18936.7 | 18936.7 | ...de stratigraphies = default; ...de matériaux et couleurs = 18 Travertin romain; ...de matériaux et couleurs - 1 = 18 Travertin romain; ...de matériaux et couleurs - 2 = 18 Travertin romain
Enveloppe 353827 | Rez-de-Jardin | 353827 | 1552655706 | 1 | 1 | 0570 | 02 | Rez-de-Jardin | no | rectangle | 58.692 | 281.4 | -1.94511e-11 | 0.691412 | 281.4 | 180.691 | HAUT Rez-de-Jardin (Rez-de-chaussée 1047) | -10 | <aucun> | Rez-de-Jardin (Rez-de-Jardin 15545) | <aucun> | 58.7 | 58.7 | 281.4 | 281.4 | 500 | 16500 | 150000 | 18 Travertin romain | 148644 | 148644 | 281.4 | 528.228 | 16515.9 | 16515.9 | ...de stratigraphies = default; ...de matériaux et couleurs = 18 Travertin romain; ...de matériaux et couleurs - 1 = 18 Travertin romain; ...de matériaux et couleurs - 2 = 18 Travertin romain
Enveloppe 568089 | Rez-de-Jardin | 568089 | 1977773087 | 1 | 1 | 0881 | 02 | Rez-de-Jardin | no | rectangle | 198.487 | 1495.01 | 7.4607e-12 | 0.282627 | 1495.01 | 180.283 | HAUT Mezzanine (Couverture 2134) | -165 | <aucun> | Rez-de-Jardin (Rez-de-Jardin 15545) | <aucun> | 198.5 | 198.5 | 1495 | 1495 | 1800 | 296800 | 2670000 | Ivoire clair | 2670666 | 2670666 | 1495.01 | 1786.38 | 296741 | 296741 | ...de stratigraphies = default; ...de matériaux et couleurs = Ivoire clair; ...de matériaux et couleurs - 1 = Ivoire clair; ...de matériaux et couleurs - 2 = Ivoire clair
Enveloppe 531419 | Rez-de-chaussée | 531419 | 1977773087 | 1 | 1 | 0849 | 03 | Rez-de-chaussée | no | rectangle | 109.904 | 479.808 | -2 | 90.0118 | 479.808 | 270.012 | HAUT Rez-de-chaussée (Niveau 1 2343) | 0.0128504 | <aucun> | Rez-de-chaussée (Rez-de-chaussée 1047) | <aucun> | 109.9 | 109.9 | 479.8 | 479.8 | 1000 | 52700 | 470000 | Ivoire clair | 474595 | 474595 | 479.808 | 989.135 | 52732.8 | 52732.8 | ...de stratigraphies = default; ...de matériaux et couleurs = Ivoire clair; ...de matériaux et couleurs - 1 = Ivoire clair; ...de matériaux et couleurs - 2 = Ivoire clair
Enveloppe 374647 | Rez-de-chaussée | 374647 | 1977773087 | 0 | 0 | 0641 | 03 | Rez-de-chaussée | no | rectangle | 97.9929 | 399.097 | 0.0128504 | 179.713 | 399.097 | 359.713 | HAUT Rez-de-chaussée (Niveau 1 2343) | -78.6853 | <aucun> | Rez-de-chaussée (Rez-de-chaussée 1047) | <aucun> | 98 | 98 | 399.1 | 399.1 | 900 | 39100 | 350000 | Ivoire clair | 351978 | 351978 | 399.097 | 881.936 | 39108.7 | 39108.7 | ...de stratigraphies = default; ...de matériaux et couleurs = Ivoire clair; ...de matériaux et couleurs - 1 = Ivoire clair; ...de matériaux et couleurs - 2 = Ivoire clair
Enveloppe 371172 | Rez-de-chaussée | 371172 | 1977773087 | 1 | 0 | 0618 | 03 | Rez-de-chaussée | no | rectangle | 126.127 | 581.511 | 0.0128504 | 89.4658 | 581.511 | 269.466 | HAUT Rez-de-chaussée (Niveau 1 2343) | 0.0128504 | <aucun> | Rez-de-chaussée (Rez-de-chaussée 1047) | sous RDC | 126.1 | 126.1 | 581.5 | 581.5 | 1100 | 73300 | 660000 | Ivoire clair | 660098 | 660098 | 581.511 | 1135.14 | 73344.3 | 73344.3 | ...de stratigraphies = default; ...de matériaux et couleurs = Ivoire clair; ...de matériaux et couleurs - 1 = Ivoire clair; ...de matériaux et couleurs - 2 = Ivoire clair
Enveloppe 119941 | Niveau 1 | 119941 | 1977773087 | 1 | 0 | 0289 | 04 | Niveau 1 | no | rectangle | 37.8646 | 376.102 | 0.0128504 | 179.387 | 376.102 | 359.387 | HAUT Niveau 1 (Niveau 2 13545) | 0 | <aucun> | Niveau 1 (Niveau 1 2343) | <aucun> | 37.9 | 37.9 | 376.1 | 376.1 | 300 | 14300 | 130000 | Ivoire clair | 128169 | 128169 | 376.102 | 340.781 | 14241 | 14241 | ...de stratigraphies = default; ...de matériaux et couleurs = Ivoire clair; ...de matériaux et couleurs - 1 = Ivoire clair; ...de matériaux et couleurs - 2 = Ivoire clair
Enveloppe 550910 | Niveau 2 | 550910 | 1977773087 | 1 | 1 | 0868 | 05 | Niveau 2 | no | trapèze | 112.476 | 256.962 | -1.95399e-11 | 89.6761 | 255 | 269.676 | Couverture (Couverture 2134) | 0 | Toit793923 | Niveau 2 (Niveau 2 13545) | <aucun> | 112.5 | 112.5 | 257 | 255 | 1000 | 28800 | 260000 | Ivoire clair | 259126 | 259126 | 255.981 | 1012.29 | 28791.8 | 28791.8 | ...de stratigraphies = default; ...de matériaux et couleurs = Ivoire clair; ...de matériaux et couleurs - 1 = Ivoire clair; ...de matériaux et couleurs - 2 = Ivoire clair
Enveloppe 734086 | Niveau 2 | 734086 | 1977773087 | 0 | 0 | 1076 | 05 | Niveau 2 | no | rectangle | 30.0981 | 235 | 1.42109e-12 | 90.9445 | 235 | 270.945 | HAUT Niveau 2 (Mezzanine 49003) | 0 | <aucun> | Niveau 2 (Niveau 2 13545) | <aucun> | 30.1 | 30.1 | 235 | 235 | 300 | 7100 | 60000 | Ivoire clair | 63657.5 | 63657.5 | 235 | 270.883 | 7073.05 | 7073.05 | ...de stratigraphies = default; ...de matériaux et couleurs = Ivoire clair; ...de matériaux et couleurs - 1 = Ivoire clair; ...de matériaux et couleurs - 2 = Ivoire clair
Enveloppe 167023 | Niveau 2 | 167023 | 1977773087 | 0 | 0 | 0408 | 05 | Niveau 2 | no | trapèze | 37.9919 | 365.651 | 1.42109e-12 | 91.0688 | 369.601 | 271.069 | HAUT Mezzanine (Couverture 2134) | 0 | Toit783918 | Niveau 2 (Niveau 2 13545) | <aucun> | 38 | 38.2 | 369.6 | 365.7 | 300 | 14000 | 130000 | Ivoire clair | 125843 | 125843 | 368.039 | 341.927 | 13982.5 | 13982.5 | ...de stratigraphies = default; ...de matériaux et couleurs = Ivoire clair; ...de matériaux et couleurs - 1 = Ivoire clair; ...de matériaux et couleurs - 2 = Ivoire clair
Enveloppe 172689 | Niveau 2 | 172689 | 1977773087 | 1 | 0 | 0437 | 05 | Niveau 2 | no | rectangle | 192.223 | 247.5 | 1.42109e-12 | 0.136662 | 247.5 | 180.137 | HAUT Niveau 2 (Mezzanine 49003) | 12.5 | <aucun> | Niveau 2 (Niveau 2 13545) | <aucun> | 192.2 | 192.2 | 247.5 | 247.5 | 1700 | 47600 | 430000 | Ivoire clair | 428177 | 428177 | 247.5 | 1730.01 | 47575.2 | 47575.2 | ...de stratigraphies = default; ...de matériaux et couleurs = Ivoire clair; ...de matériaux et couleurs - 1 = Ivoire clair; ...de matériaux et couleurs - 2 = Ivoire clair
Enveloppe 172941 | Niveau 2 | 172941 | 1977773087 | 1 | 0 | 0441 | 05 | Niveau 2 | no | rectangle | 165.594 | 247.5 | 1.42109e-12 | 0.434934 | 247.5 | 180.435 | HAUT Niveau 2 (Mezzanine 49003) | 12.5 | <aucun> | Niveau 2 (Niveau 2 13545) | <aucun> | 165.6 | 165.6 | 247.5 | 247.5 | 1500 | 41000 | 370000 | Ivoire clair | 368860 | 368860 | 247.5 | 1490.34 | 40984.4 | 40984.4 | ...de stratigraphies = default; ...de matériaux et couleurs = Ivoire clair; ...de matériaux et couleurs - 1 = Ivoire clair; ...de matériaux et couleurs - 2 = Ivoire clair

# IfcWallStandardCase: default 100 (29)
Type - Material: <aucun> 10 cm
__RECOGNIZE__ - GENERATE: 1
CTLG_EXTERNAL_LINK - 0, DocType: 2; 0, Tag: 0; 1, DocType: 2; 1, Tag: 100; 2, DocType: 2; 2, Tag: 200; 3, DocType: 9; 3, Tag: 0; 3, Crc: 1364580673
IFC_PSET_PolygonOffset - polygonOffsetFactor: 2; polygonOffsetUnits: 2
IFC_Pset_Caractéristiques - Stratigraphie: default [100,00]; Épaisseur: 10 cm
IFC_Pset_Caractéristiques_FRUIT - Fruit: no; Taille: 0 cm
IFC_Pset_Géométrie - Forme en Élévation: rectangle
IFC_Pset_Système de Référence Altimétrique_SUPÉRIEUR - sous Niveau: <aucun>
IFC_Pset_Système de Référence Altimétrique_INFÉRIEUR - sous Niveau: <aucun>
Pset_WallCommon - Reference: default [100,00] (..\VERTICALES\Default\)
BaseQuantities - NominalWidth: 10 cm
Name | In | Description | __RECOGNIZE__, ID = IFC_Pset_Caractéristiques, ID | TPLG | TPLG_OD | 0, Crc = 1, Crc = 2, Crc | Alignment | ExternalFace | Numérotation | Numéro niveau | Titre niveau | Épaisseur VARIABLE | Longueur (cm) = NominalLength (cm) | IFC_Pset_Géométrie, Hauteur (cm) = IFC_Pset_Géométrie_P1 (POINT initial), Hauteur (cm) = IFC_Pset_Géométrie_P2 (POINT final), Hauteur (cm) = NominalHeight (cm) | IFC_Pset_Géométrie, Cote (cm) = IFC_Pset_Géométrie_P1 (POINT initial), Cote (cm) = IFC_Pset_Géométrie_P2 (POINT final), Cote (cm) = IFC_Pset_Système de Référence Altimétrique_INFÉRIEUR, delta (cm) = IFC_Pset_Système de Référence Altimétrique_INFÉRIEUR, delta (P1) (cm) = IFC_Pset_Système de Référence Altimétrique_INFÉRIEUR, delta (P2) (cm) | IFC_Pset_Géométrie_P1 (POINT initial), Angle XY (deg) | IFC_Pset_Géométrie_P2 (POINT final), Angle XY (deg) | IFC_Pset_Système de Référence Altimétrique_SUPÉRIEUR, NIVEAU | IFC_Pset_Système de Référence Altimétrique_SUPÉRIEUR, delta (cm) = IFC_Pset_Système de Référence Altimétrique_SUPÉRIEUR, delta (P1) (cm) = IFC_Pset_Système de Référence Altimétrique_SUPÉRIEUR, delta (P2) (cm) | IFC_Pset_Système de Référence Altimétrique_INFÉRIEUR, NIVEAU | Longueur Pied (cm) = Longueur Tête (cm) | Hauteur Maximale (cm) = Hauteur Minimale (cm) | Surface en Plan (cm2) = Surface Pied (cm2) = Surface Tête (cm2) | Surface de la Paroi (cm2) | Volume (cm3) | Face gauche = Face droite = Face latérale | GrossVolume (cm3) | NetVolume (cm3) | GrossFootprintArea (cm2) = NetFootprintArea (cm2) | GrossSideArea (cm2) | NetSideArea (cm2) | Group
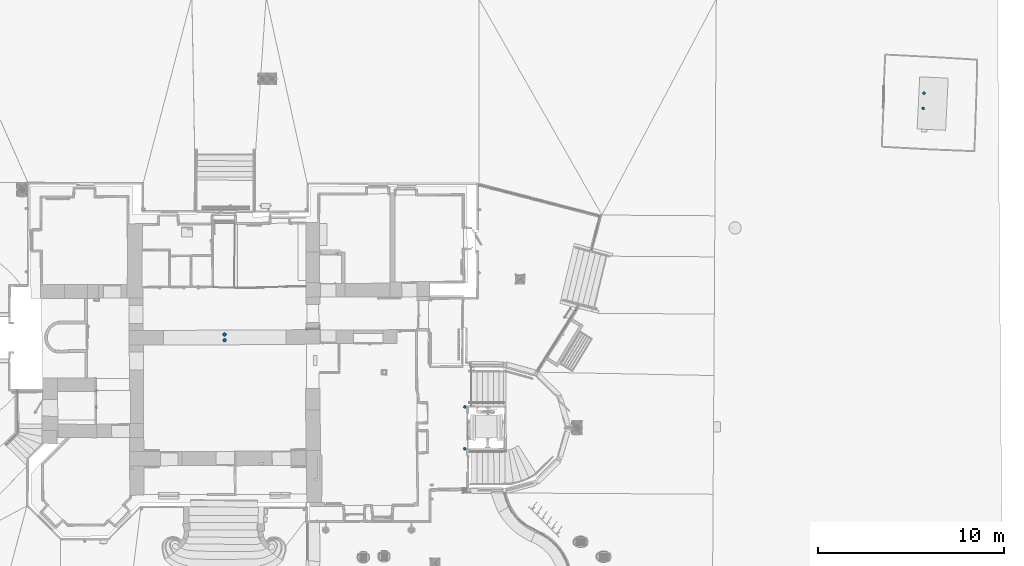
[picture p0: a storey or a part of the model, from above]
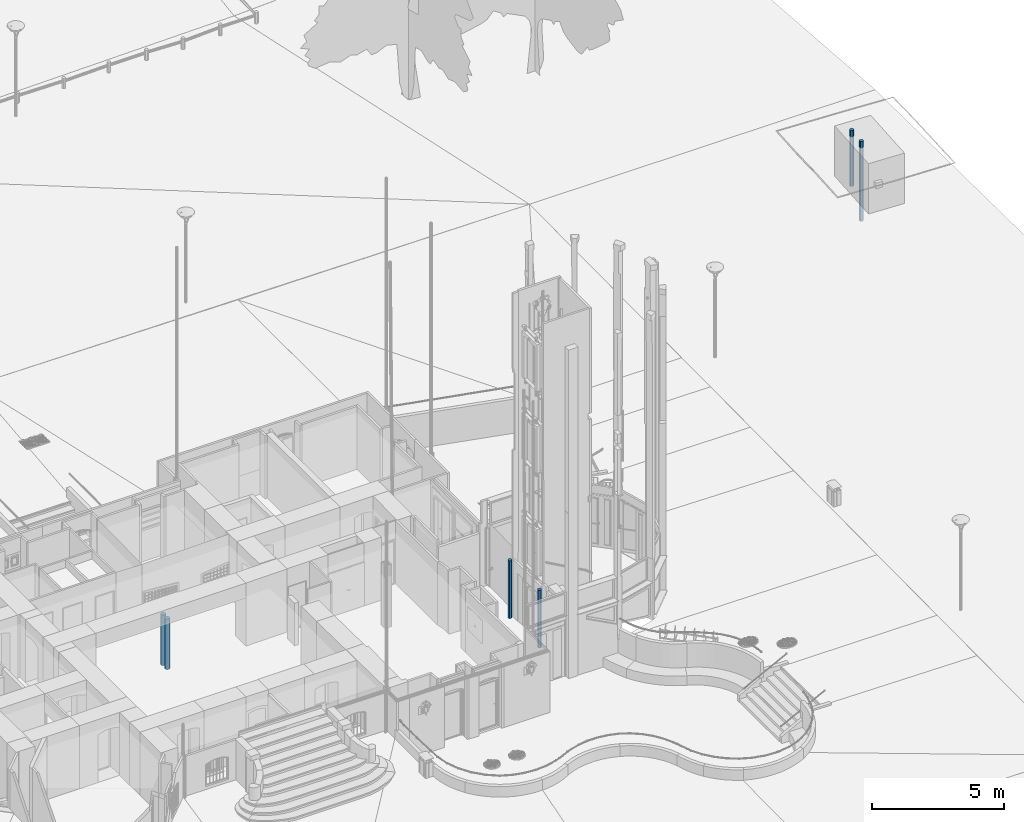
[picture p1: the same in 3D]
Properties of the parts of a building model (IFC2X3), part 20 of 37

# IfcWallStandardCase: default 100 (29)
Name | In | Description | __RECOGNIZE__, ID = IFC_Pset_Caractéristiques, ID | TPLG | TPLG_OD | 0, Crc = 1, Crc = 2, Crc | Alignment | ExternalFace | Numérotation | Numéro niveau | Titre niveau | Épaisseur VARIABLE | Longueur (cm) = NominalLength (cm) | IFC_Pset_Géométrie, Hauteur (cm) = IFC_Pset_Géométrie_P1 (POINT initial), Hauteur (cm) = IFC_Pset_Géométrie_P2 (POINT final), Hauteur (cm) = NominalHeight (cm) | IFC_Pset_Géométrie, Cote (cm) = IFC_Pset_Géométrie_P1 (POINT initial), Cote (cm) = IFC_Pset_Géométrie_P2 (POINT final), Cote (cm) = IFC_Pset_Système de Référence Altimétrique_INFÉRIEUR, delta (cm) = IFC_Pset_Système de Référence Altimétrique_INFÉRIEUR, delta (P1) (cm) = IFC_Pset_Système de Référence Altimétrique_INFÉRIEUR, delta (P2) (cm) | IFC_Pset_Géométrie_P1 (POINT initial), Angle XY (deg) | IFC_Pset_Géométrie_P2 (POINT final), Angle XY (deg) | IFC_Pset_Système de Référence Altimétrique_SUPÉRIEUR, NIVEAU | IFC_Pset_Système de Référence Altimétrique_SUPÉRIEUR, delta (cm) = IFC_Pset_Système de Référence Altimétrique_SUPÉRIEUR, delta (P1) (cm) = IFC_Pset_Système de Référence Altimétrique_SUPÉRIEUR, delta (P2) (cm) | IFC_Pset_Système de Référence Altimétrique_INFÉRIEUR, NIVEAU | Longueur Pied (cm) = Longueur Tête (cm) | Hauteur Maximale (cm) = Hauteur Minimale (cm) | Surface en Plan (cm2) = Surface Pied (cm2) = Surface Tête (cm2) | Surface de la Paroi (cm2) | Volume (cm3) | Face gauche = Face droite = Face latérale | GrossVolume (cm3) | NetVolume (cm3) | GrossFootprintArea (cm2) = NetFootprintArea (cm2) | GrossSideArea (cm2) | NetSideArea (cm2) | Group
Enveloppe 72368 | Rez-de-Jardin | Enveloppe | 72368 | 366 | 9000 | 1977773087 | 0 | 0 | 0160 | 02 | Rez-de-Jardin | no | 149.328 | 271.4 | -1.94511e-11 | 90.7647 | 270.765 | HAUT Rez-de-Jardin (Rez-de-chaussée 1047) | -20 | Rez-de-Jardin (Rez-de-Jardin 15545) | 149.3 | 271.4 | 1500 | 40500 | 410000 | Ivoire clair | 405276 | 376823 | 1493.28 | 40527.6 | 37682.3 | ...de stratigraphies = default; ...de matériaux et couleurs = Ivoire clair; ...de matériaux et couleurs - 1 = Ivoire clair; ...de matériaux et couleurs - 2 = Ivoire clair
Enveloppe 13547 | Rez-de-chaussée | Enveloppe | 13547 | 366 | 9000 | 1977773087 | 1 | 0 | 0053 | 03 | Rez-de-chaussée | no | 47.2276 | 271.483 | 0.0128504 | 91.023 | 271.023 | HAUT Rez-de-chaussée (Niveau 1 2343) | -206.3 | Rez-de-chaussée (Rez-de-chaussée 1047) | 47.2 | 271.5 | 500 | 12800 | 130000 | Ivoire clair | 128215 | 128215 | 472.276 | 12821.5 | 12821.5 | ...de stratigraphies = default; ...de matériaux et couleurs = Ivoire clair; ...de matériaux et couleurs - 1 = Ivoire clair; ...de matériaux et couleurs - 2 = Ivoire clair
Enveloppe 44912 | Rez-de-chaussée | Enveloppe | 44912 | 366 | 9000 | 1977773087 | 0 | 0 | 0073 | 03 | Rez-de-chaussée | no | 41.2913 | 477.795 | 0.0128504 | 0.0255063 | 180.026 | HAUT Rez-de-chaussée (Niveau 1 2343) | 0.0128504 | Rez-de-chaussée (Rez-de-chaussée 1047) | 41.3 | 477.8 | 400 | 19700 | 200000 | Ivoire clair | 197288 | 197288 | 412.913 | 19728.8 | 19728.8 | ...de stratigraphies = default; ...de matériaux et couleurs = Ivoire clair; ...de matériaux et couleurs - 1 = Ivoire clair; ...de matériaux et couleurs - 2 = Ivoire clair
Enveloppe 29281 | Rez-de-chaussée | Enveloppe | 29281 | 366 | 9000 | 1977773087 | 0 | 0 | 0059 | 03 | Rez-de-chaussée | yes | 99.4772 | 264.987 | 0.0128504 | 0.201098 | 180.201 | HAUT Rez-de-chaussée (Niveau 1 2343) | -212.795 | Rez-de-chaussée (Rez-de-chaussée 1047) | 99.5 | 265 | 1000 | 26400 | 260000 | Ivoire clair | 263602 | 71513.4 | 994.772 | 26360.2 | 7151.34 | ...de stratigraphies = default; ...de matériaux et couleurs = Ivoire clair; ...de matériaux et couleurs - 1 = Ivoire clair; ...de matériaux et couleurs - 2 = Ivoire clair
Enveloppe 3475 | Rez-de-chaussée | Enveloppe | 3475 | 366 | 9000 | 1977773087 | 0 | 0 | 0031 | 03 | Rez-de-chaussée | no | 138.859 | 477.795 | 0.0128504 | 90.4339 | 270.434 | HAUT Rez-de-chaussée (Niveau 1 2343) | 0.0128504 | Rez-de-chaussée (Rez-de-chaussée 1047) | 138.9 | 477.8 | 1400 | 66400 | 660000 | Ivoire clair | 663461 | 663461 | 1388.59 | 66346.1 | 66346.1 | ...de stratigraphies = default; ...de matériaux et couleurs = Ivoire clair; ...de matériaux et couleurs - 1 = Ivoire clair; ...de matériaux et couleurs - 2 = Ivoire clair
Enveloppe 738299 | Niveau 2 | Enveloppe | 738299 | 366 | 9000 | 1977773087 | 1 | 1 | 1079 | 05 | Niveau 2 | no | 146.942 | 235 | -1.95399e-11 | 179.869 | 359.869 | HAUT Niveau 2 (Mezzanine 49003) | 7.99361e-12 | Niveau 2 (Niveau 2 13545) | 146.9 | 235 | 1500 | 34500 | 350000 | Ivoire clair | 345313 | 235685 | 1469.42 | 34531.3 | 23568.5 | ...de stratigraphies = default; ...de matériaux et couleurs = Ivoire clair; ...de matériaux et couleurs - 1 = Ivoire clair; ...de matériaux et couleurs - 2 = Ivoire clair
Enveloppe 177845 | Niveau 2 | Enveloppe | 177845 | 366 | 9000 | 1977773087 | 0 | 0 | 0463 | 05 | Niveau 2 | yes | 24.6501 | 235 | 1.42109e-12 | 90.601 | 270.601 | HAUT Niveau 2 (Mezzanine 49003) | 0 | Niveau 2 (Niveau 2 13545) | 24.7 | 235 | 200 | 5800 | 60000 | Ivoire clair | 57927.8 | 57927.8 | 246.501 | 5792.78 | 5792.78 | ...de stratigraphies = default; ...de matériaux et couleurs = Ivoire clair; ...de matériaux et couleurs - 1 = Ivoire clair; ...de matériaux et couleurs - 2 = Ivoire clair
Enveloppe 180013 | Niveau 2 | Enveloppe | 180013 | 366 | 9000 | 1977773087 | 0 | 0 | 0468 | 05 | Niveau 2 | no | 136.068 | 208 | 1.06581e-12 | 90.534 | 270.534 | HAUT Niveau 2 (Mezzanine 49003) | -27 | Niveau 2 (Niveau 2 13545) | 136.1 | 208 | 1400 | 28300 | 280000 | Ivoire clair | 283021 | 124056 | 1360.68 | 28302.1 | 12405.6 | ...de stratigraphies = default; ...de matériaux et couleurs = Ivoire clair; ...de matériaux et couleurs - 1 = Ivoire clair; ...de matériaux et couleurs - 2 = Ivoire clair
Enveloppe 151906 | Niveau 2 | Enveloppe | 151906 | 366 | 9000 | 1977773087 | 0 | 0 | 0351 | 05 | Niveau 2 | no | 114.94 | 235 | 1.42109e-12 | 0.649835 | 180.65 | HAUT Niveau 2 (Mezzanine 49003) | 0 | Niveau 2 (Niveau 2 13545) | 114.9 | 235 | 1100 | 27000 | 270000 | Ivoire clair | 270108 | 65969.7 | 1149.4 | 27010.8 | 6596.97 | ...de stratigraphies = default; ...de matériaux et couleurs = Ivoire clair; ...de matériaux et couleurs - 1 = Ivoire clair; ...de matériaux et couleurs - 2 = Ivoire clair
Enveloppe 158985 | Niveau 2 | Enveloppe | 158985 | 366 | 9000 | 1977773087 | 1 | 0 | 0368 | 05 | Niveau 2 | no | 58.5037 | 235 | 1.42109e-12 | 88.5008 | 268.501 | HAUT Niveau 2 (Mezzanine 49003) | 0 | Niveau 2 (Niveau 2 13545) | 58.5 | 235 | 600 | 13700 | 140000 | Ivoire clair | 137484 | 137484 | 585.037 | 13748.4 | 13748.4 | ...de stratigraphies = default; ...de matériaux et couleurs = Ivoire clair; ...de matériaux et couleurs - 1 = Ivoire clair; ...de matériaux et couleurs - 2 = Ivoire clair
Enveloppe 158968 | Niveau 2 | Enveloppe | 158968 | 366 | 9000 | 1977773087 | 1 | 0 | 0367 | 05 | Niveau 2 | no | 213.495 | 235 | 1.42109e-12 | 0.198169 | 180.198 | HAUT Niveau 2 (Mezzanine 49003) | 0 | Niveau 2 (Niveau 2 13545) | 213.5 | 235 | 2100 | 50200 | 500000 | Ivoire clair | 501713 | 501713 | 2134.95 | 50171.3 | 50171.3 | ...de stratigraphies = default; ...de matériaux et couleurs = Ivoire clair; ...de matériaux et couleurs - 1 = Ivoire clair; ...de matériaux et couleurs - 2 = Ivoire clair
Enveloppe 159096 | Niveau 2 | Enveloppe | 159096 | 366 | 9000 | 1977773087 | 1 | 0 | 0371 | 05 | Niveau 2 | no | 24.9313 | 235 | 1.42109e-12 | 89.4168 | 269.417 | HAUT Niveau 2 (Mezzanine 49003) | 0 | Niveau 2 (Niveau 2 13545) | 24.9 | 235 | 200 | 5900 | 60000 | Ivoire clair | 58588.6 | 58588.6 | 249.313 | 5858.86 | 5858.86 | ...de stratigraphies = default; ...de matériaux et couleurs = Ivoire clair; ...de matériaux et couleurs - 1 = Ivoire clair; ...de matériaux et couleurs - 2 = Ivoire clair
Enveloppe 159127 | Niveau 2 | Enveloppe | 159127 | 366 | 9000 | 1977773087 | 1 | 0 | 0372 | 05 | Niveau 2 | no | 153.636 | 261.846 | 1.42109e-12 | 134.823 | 314.823 | HAUT Niveau 2 (Mezzanine 49003) | 26.8456 | Niveau 2 (Niveau 2 13545) | 153.6 | 261.8 | 1500 | 40200 | 400000 | Ivoire clair | 402289 | 240823 | 1536.36 | 40228.9 | 24082.3 | ...de stratigraphies = default; ...de matériaux et couleurs = Ivoire clair; ...de matériaux et couleurs - 1 = Ivoire clair; ...de matériaux et couleurs - 2 = Ivoire clair
Enveloppe 194511 | Mezzanine | Enveloppe | 194511 | 366 | 9000 | -1156274542 | 0 | 1 | 0482 | 06 | Mezzanine | yes | 42.6136 | 159.702 | 3.73035e-12 | 90.0308 | 270.031 | HAUT Mezzanine (Couverture 2134) | -120 | Mezzanine (Mezzanine 49003) | 42.6 | 159.7 | 400 | 6800 | 70000 | Chêne | 68055 | 68055 | 426.136 | 6805.5 | 6805.5 | ...de matériaux et couleurs = Chêne; ...de stratigraphies = default; ...de matériaux et couleurs - 1 = Chêne; ...de matériaux et couleurs - 2 = Chêne
Enveloppe 192057 | Mezzanine | Enveloppe | 192057 | 366 | 9000 | -1156274542 | 0 | 1 | 0473 | 06 | Mezzanine | no | 898.387 | 55 | -5 | 0.492332 | 180.492 | HAUT Mezzanine (Couverture 2134) | -229.702 | Mezzanine (Mezzanine 49003) | 898.4 | 55 | 8900 | 49400 | 490000 | Chêne | 494113 | 494113 | 8983.87 | 49411.3 | 49411.3 | ...de matériaux et couleurs = Chêne; ...de stratigraphies = default; ...de matériaux et couleurs - 1 = Chêne; ...de matériaux et couleurs - 2 = Chêne
Enveloppe 2027986 | Mezzanine | Enveloppe | 2027986 | 366 | 9000 | -1156274542 | 1 | 1 | 1177 | 06 | Mezzanine | no | 24.4894 | 55 | -5 | 0.341117 | 180.341 | HAUT Mezzanine (Couverture 2134) | -229.702 | Mezzanine (Mezzanine 49003) | 24.5 | 55 | 200 | 1300 | 10000 | Chêne | 13469.1 | 13469.1 | 244.894 | 1346.91 | 1346.91 | ...de matériaux et couleurs = Chêne; ...de stratigraphies = default; ...de matériaux et couleurs - 1 = Chêne; ...de matériaux et couleurs - 2 = Chêne
Enveloppe 201194 | Mezzanine | Enveloppe | 201194 | 366 | 9000 | -1156274542 | 1 | 1 | 0505 | 06 | Mezzanine | no | 845.142 | 55 | -5 | 0.341117 | 180.341 | HAUT Mezzanine (Couverture 2134) | -229.702 | Mezzanine (Mezzanine 49003) | 845.1 | 55 | 8500 | 46500 | 470000 | Chêne | 464828 | 464828 | 8451.42 | 46482.8 | 46482.8 | ...de matériaux et couleurs = Chêne; ...de stratigraphies = default; ...de matériaux et couleurs - 1 = Chêne; ...de matériaux et couleurs - 2 = Chêne
Muret 794449 | Couverture | _MRT_Muret | 794449 | 441 | 9010 | 1164012461 | 1 | 0 | 22 | 07 | Couverture | no | 108.633 | 10 | 105 | 179.972 | 359.972 | (Couverture 2134 <aucun>) | 115 | Couverture (Couverture 2134) | 108.6 | 10 | 1100 | 1100 | 10000 | Brique (01) | 10863.3 | 10863.3 | 1086.33 | 1086.33 | 1086.33 | ...de stratigraphies = default; ...de matériaux et couleurs = Brique (01); ...de matériaux et couleurs - 1 = Brique (01); ...de matériaux et couleurs - 2 = Brique (01)
Muret 794455 | Couverture | _MRT_Muret | 794455 | 441 | 9010 | 1164012461 | 0 | 0 | 23 | 07 | Couverture | no | 46.1972 | 10 | 105 | 88.9515 | 268.952 | (Couverture 2134 <aucun>) | 115 | Couverture (Couverture 2134) | 46.2 | 10 | 500 | 500 | 10000 | Brique (01) | 4619.72 | 4619.72 | 461.972 | 461.972 | 461.972 | ...de stratigraphies = default; ...de matériaux et couleurs = Brique (01); ...de matériaux et couleurs - 1 = Brique (01); ...de matériaux et couleurs - 2 = Brique (01)
Muret 794468 | Couverture | _MRT_Muret | 794468 | 441 | 9010 | 1164012461 | 0 | 0 | 24 | 07 | Couverture | no | 118.475 | 10 | 105 | 179.981 | 359.981 | (Couverture 2134 <aucun>) | 115 | Couverture (Couverture 2134) | 118.5 | 10 | 1200 | 1200 | 10000 | Brique (01) | 11847.5 | 11847.5 | 1184.75 | 1184.75 | 1184.75 | ...de stratigraphies = default; ...de matériaux et couleurs = Brique (01); ...de matériaux et couleurs - 1 = Brique (01); ...de matériaux et couleurs - 2 = Brique (01)
Muret 794443 | Couverture | _MRT_Muret | 794443 | 441 | 9010 | 1164012461 | 1 | 0 | 21 | 07 | Couverture | no | 36.1826 | 10 | 105 | 88.7045 | 268.705 | (Couverture 2134 <aucun>) | 115 | Couverture (Couverture 2134) | 36.2 | 10 | 400 | 400 | 0 | Brique (01) | 3618.26 | 3618.26 | 361.826 | 361.826 | 361.826 | ...de stratigraphies = default; ...de matériaux et couleurs = Brique (01); ...de matériaux et couleurs - 1 = Brique (01); ...de matériaux et couleurs - 2 = Brique (01)
Muret 782916 | Couverture | _MRT_Muret | 782916 | 441 | 9010 | 1164012461 | 0 | 0 | 05 | 07 | Couverture | no | 53.031 | 10 | 100 | 138.522 | 318.522 | (Couverture 2134 <aucun>) | 110 | Couverture (Couverture 2134) | 53 | 10 | 500 | 500 | 10000 | Brique (01) | 5303.1 | 5303.1 | 530.31 | 530.31 | 530.31 | ...de stratigraphies = default; ...de matériaux et couleurs = Brique (01); ...de matériaux et couleurs - 1 = Brique (01); ...de matériaux et couleurs - 2 = Brique (01)
Muret 782917 | Couverture | _MRT_Muret | 782917 | 441 | 9010 | 1164012461 | 1 | 0 | 06 | 07 | Couverture | no | 55.4487 | 10 | 100 | 134.393 | 314.393 | (Couverture 2134 <aucun>) | 110 | Couverture (Couverture 2134) | 55.4 | 10 | 600 | 600 | 10000 | Brique (01) | 5544.87 | 5544.87 | 554.487 | 554.487 | 554.487 | ...de stratigraphies = default; ...de matériaux et couleurs = Brique (01); ...de matériaux et couleurs - 1 = Brique (01); ...de matériaux et couleurs - 2 = Brique (01)
Muret 783312 | Couverture | _MRT_Muret | 783312 | 441 | 9010 | 1164012461 | 1 | 0 | 10 | 07 | Couverture | no | 123.012 | 10 | 115 | 89.2513 | 269.251 | (Couverture 2134 <aucun>) | 125 | Couverture (Couverture 2134) | 123 | 10 | 1200 | 1200 | 10000 | Brique (01) | 12301.2 | 12301.2 | 1230.12 | 1230.12 | 1230.12 | ...de stratigraphies = default; ...de matériaux et couleurs = Brique (01); ...de matériaux et couleurs - 1 = Brique (01); ...de matériaux et couleurs - 2 = Brique (01)
Muret 783317 | Couverture | _MRT_Muret | 783317 | 441 | 9010 | 1164012461 | 1 | 0 | 11 | 07 | Couverture | no | 51.8308 | 10 | 115 | 0.143707 | 180.144 | (Couverture 2134 <aucun>) | 125 | Couverture (Couverture 2134) | 51.8 | 10 | 500 | 500 | 10000 | Brique (01) | 5183.08 | 5183.08 | 518.308 | 518.308 | 518.308 | ...de stratigraphies = default; ...de matériaux et couleurs = Brique (01); ...de matériaux et couleurs - 1 = Brique (01); ...de matériaux et couleurs - 2 = Brique (01)
Muret 783322 | Couverture | _MRT_Muret | 783322 | 441 | 9010 | 1164012461 | 0 | 0 | 12 | 07 | Couverture | no | 124.143 | 10 | 115 | 89.2819 | 269.282 | (Couverture 2134 <aucun>) | 125 | Couverture (Couverture 2134) | 124.1 | 10 | 1200 | 1200 | 10000 | Brique (01) | 12414.3 | 12414.3 | 1241.43 | 1241.43 | 1241.43 | ...de stratigraphies = default; ...de matériaux et couleurs = Brique (01); ...de matériaux et couleurs - 1 = Brique (01); ...de matériaux et couleurs - 2 = Brique (01)
Muret 782918 | Couverture | _MRT_Muret | 782918 | 441 | 9010 | 1164012461 | 0 | 0 | 07 | 07 | Couverture | no | 76.959 | 10 | 100 | 45.4306 | 225.431 | (Couverture 2134 <aucun>) | 110 | Couverture (Couverture 2134) | 77 | 10 | 800 | 800 | 10000 | Brique (01) | 7695.9 | 7695.9 | 769.59 | 769.59 | 769.59 | ...de stratigraphies = default; ...de matériaux et couleurs = Brique (01); ...de matériaux et couleurs - 1 = Brique (01); ...de matériaux et couleurs - 2 = Brique (01)
Muret 782919 | Couverture | _MRT_Muret | 782919 | 441 | 9010 | 1164012461 | 1 | 0 | 08 | 07 | Couverture | no | 84.5858 | 10 | 100 | 43.4518 | 223.452 | (Couverture 2134 <aucun>) | 110 | Couverture (Couverture 2134) | 84.6 | 10 | 800 | 800 | 10000 | Brique (01) | 8458.58 | 8458.58 | 845.858 | 845.858 | 845.858 | ...de stratigraphies = default; ...de matériaux et couleurs = Brique (01); ...de matériaux et couleurs - 1 = Brique (01); ...de matériaux et couleurs - 2 = Brique (01)
Muret 783260 | Couverture | _MRT_Muret | 783260 | 441 | 9010 | 1164012461 | 1 | 0 | 09 | 07 | Couverture | no | 51.8951 | 10 | 115 | 178.893 | 358.893 | (Couverture 2134 <aucun>) | 125 | Couverture (Couverture 2134) | 51.9 | 10 | 500 | 500 | 10000 | Brique (01) | 5189.51 | 5189.51 | 518.951 | 518.951 | 518.951 | ...de stratigraphies = default; ...de matériaux et couleurs = Brique (01); ...de matériaux et couleurs - 1 = Brique (01); ...de matériaux et couleurs - 2 = Brique (01)

# IfcWallStandardCase: default 105, Enveloppe 159163
In: Niveau 2
Type - Material: <aucun> 10.5 cm
Description: Enveloppe; Group: ...de stratigraphies = default; ...de matériaux et couleurs = Ivoire clair; ...de matériaux et couleurs - 1 = Ivoire clair; ...de matériaux et couleurs - 2 = Ivoire clair
__RECOGNIZE__ - ID: 159163; TPLG: 366; TPLG_OD: 9000; GENERATE: 1
CTLG_EXTERNAL_LINK - 0, DocType: 2; 0, Tag: 0; 0, Crc: 1977773087; 1, DocType: 2; 1, Tag: 100; 1, Crc: 1977773087; 2, DocType: 2; 2, Tag: 200; 2, Crc: 1977773087; 3, DocType: 9; 3, Tag: 0; 3, Crc: 1028494013
IFC_PSET_PolygonOffset - polygonOffsetFactor: 2; polygonOffsetUnits: 2
IFC_Pset_Alignment - Alignment: 1
IFC_Pset_Strat_Detail_Align - ExternalFace: 0
IFC_Pset_Caractéristiques - ID: 159163; Numérotation: 0373; Numéro niveau: 05; Titre niveau: Niveau 2; Stratigraphie: default [105,00]; Épaisseur: 10.5 cm; Épaisseur VARIABLE: no
IFC_Pset_Caractéristiques_FRUIT - Fruit: no; Taille: 0 cm
IFC_Pset_Géométrie - Forme en Élévation: rectangle; Longueur: 59.0868 cm; Hauteur: 261.398 cm; Cote: 1.42109e-12 cm
IFC_Pset_Géométrie_P1 (POINT initial) - Hauteur: 261.398 cm; Cote: 1.42109e-12 cm; Angle XY: 134.823 deg
IFC_Pset_Géométrie_P2 (POINT final) - Hauteur: 261.398 cm; Cote: 1.42109e-12 cm; Angle XY: 314.823 deg
IFC_Pset_Système de Référence Altimétrique_SUPÉRIEUR - NIVEAU: HAUT Niveau 2 (Mezzanine 49003); delta: 26.3977 cm; delta (P1): 26.3977 cm; delta (P2): 26.3977 cm; sous Niveau: <aucun>
IFC_Pset_Système de Référence Altimétrique_INFÉRIEUR - NIVEAU: Niveau 2 (Niveau 2 13545); delta: 1.42109e-12 cm; delta (P1): 1.42109e-12 cm; delta (P2): 1.42109e-12 cm; sous Niveau: <aucun>
IFC_Pset_Données Métré - Longueur Pied: 59.1 cm; Longueur Tête: 59.1 cm; Hauteur Maximale: 261.4 cm; Hauteur Minimale: 261.4 cm; Surface en Plan: 700 cm2; Surface Pied: 700 cm2; Surface Tête: 700 cm2; Surface de la Paroi: 15400 cm2; Volume: 170000 cm3
IFC_Pset_Matériaux - Face gauche: Ivoire clair; Face droite: Ivoire clair; Face latérale: Ivoire clair
Pset_WallCommon - Reference: default [105,00] (..\VERTICALES\Default\)
BaseQuantities - GrossVolume: 162174 cm3; NetVolume: 162174 cm3; NominalLength: 59.0868 cm; NominalWidth: 10.5 cm; NominalHeight: 261.398 cm; GrossFootprintArea: 620.411 cm2; NetFootprintArea: 620.411 cm2; GrossSideArea: 15445.1 cm2; NetSideArea: 15445.1 cm2

# IfcWallStandardCase: default 110 (2)
In: Rez-de-chaussée
Type - Material: <aucun> 11 cm
Description: Enveloppe; Group: ...de stratigraphies = default; ...de matériaux et couleurs = Ivoire clair; ...de matériaux et couleurs - 1 = Ivoire clair; ...de matériaux et couleurs - 2 = Ivoire clair
__RECOGNIZE__ - TPLG: 366; TPLG_OD: 9000; GENERATE: 1
CTLG_EXTERNAL_LINK - 0, DocType: 2; 0, Tag: 0; 0, Crc: 1977773087; 1, DocType: 2; 1, Tag: 100; 1, Crc: 1977773087; 2, DocType: 2; 2, Tag: 200; 2, Crc: 1977773087; 3, DocType: 9; 3, Tag: 0; 3, Crc: 1943053697
IFC_PSET_PolygonOffset - polygonOffsetFactor: 2; polygonOffsetUnits: 2
IFC_Pset_Alignment - Alignment: 1
IFC_Pset_Strat_Detail_Align - ExternalFace: 0
IFC_Pset_Caractéristiques - Numéro niveau: 03; Titre niveau: Rez-de-chaussée; Stratigraphie: default [110,00]; Épaisseur: 11 cm; Épaisseur VARIABLE: no
IFC_Pset_Caractéristiques_FRUIT - Fruit: no; Taille: 0 cm
IFC_Pset_Géométrie - Cote: 0.0128504 cm
IFC_Pset_Géométrie_P1 (POINT initial) - Cote: 0.0128504 cm
IFC_Pset_Géométrie_P2 (POINT final) - Cote: 0.0128504 cm
IFC_Pset_Système de Référence Altimétrique_SUPÉRIEUR - NIVEAU: HAUT Rez-de-chaussée (Niveau 1 2343); sous Niveau: <aucun>
IFC_Pset_Système de Référence Altimétrique_INFÉRIEUR - NIVEAU: Rez-de-chaussée (Rez-de-chaussée 1047); delta: 0.0128504 cm; delta (P1): 0.0128504 cm; delta (P2): 0.0128504 cm
IFC_Pset_Matériaux - Face gauche: Ivoire clair; Face droite: Ivoire clair; Face latérale: Ivoire clair
Pset_WallCommon - Reference: default [110,00] (..\VERTICALES\Default\)
BaseQuantities - NominalWidth: 11 cm
Name | __RECOGNIZE__, ID = IFC_Pset_Caractéristiques, ID | Numérotation | Forme en Élévation | Longueur (cm) = NominalLength (cm) | IFC_Pset_Géométrie, Hauteur (cm) = IFC_Pset_Géométrie_P1 (POINT initial), Hauteur (cm) | IFC_Pset_Géométrie_P1 (POINT initial), Angle XY (deg) | IFC_Pset_Géométrie_P2 (POINT final), Hauteur (cm) | IFC_Pset_Géométrie_P2 (POINT final), Angle XY (deg) | delta (cm) = delta (P1) (cm) = delta (P2) (cm) | sous Niveau | Longueur Pied (cm) | Longueur Tête (cm) | Hauteur Maximale (cm) | Hauteur Minimale (cm) | Surface en Plan (cm2) = Surface Pied (cm2) | Surface Tête (cm2) | Surface de la Paroi (cm2) | Volume (cm3) | GrossVolume (cm3) = NetVolume (cm3) | NominalHeight (cm) | GrossFootprintArea (cm2) = NetFootprintArea (cm2) | GrossSideArea (cm2) = NetSideArea (cm2)
Enveloppe 78848 | 78848 | 0178 | rectangle | 219.62 | 103.715 | 0.267433 | 103.715 | 180.267 | -477.783 | sous RDC | 219.6 | 219.6 | 103.7 | 103.7 | 2400 | 2400 | 22800 | 250000 | 250558 | 103.715 | 2415.82 | 22778
Enveloppe 2397 | 2397 | 0002 | trapèze | 304.306 | 62.3843 | 179.882 | 185.879 | 359.882 | 0 | <aucun> | 304.3 | 328.4 | 185.9 | 62.4 | 3300 | 3700 | 44200 | 490000 | 486861 | 145.446 | 3347.37 | 44260.1

# IfcWallStandardCase: default 120 (11)
Type - Material: <aucun> 12 cm
Description: Enveloppe
__RECOGNIZE__ - TPLG: 366; TPLG_OD: 9000; GENERATE: 1
CTLG_EXTERNAL_LINK - 0, DocType: 2; 0, Tag: 0; 1, DocType: 2; 1, Tag: 100; 2, DocType: 2; 2, Tag: 200; 3, DocType: 9; 3, Tag: 0; 3, Crc: 624124834
IFC_PSET_PolygonOffset - polygonOffsetFactor: 2; polygonOffsetUnits: 2
IFC_Pset_Caractéristiques - Stratigraphie: default [120,00]; Épaisseur: 12 cm
IFC_Pset_Caractéristiques_FRUIT - Fruit: no; Taille: 0 cm
IFC_Pset_Système de Référence Altimétrique_INFÉRIEUR - sous Niveau: <aucun>
Pset_WallCommon - Reference: default [120,00] (..\VERTICALES\Default\)
BaseQuantities - NominalWidth: 12 cm
Name | In | __RECOGNIZE__, ID = IFC_Pset_Caractéristiques, ID | 0, Crc = 1, Crc = 2, Crc | Alignment | ExternalFace | Numérotation | Numéro niveau | Titre niveau | Épaisseur VARIABLE | Forme en Élévation | Longueur (cm) = NominalLength (cm) | IFC_Pset_Géométrie, Hauteur (cm) = IFC_Pset_Géométrie_P1 (POINT initial), Hauteur (cm) | IFC_Pset_Géométrie, Cote (cm) = IFC_Pset_Géométrie_P1 (POINT initial), Cote (cm) = IFC_Pset_Géométrie_P2 (POINT final), Cote (cm) = IFC_Pset_Système de Référence Altimétrique_INFÉRIEUR, delta (cm) = IFC_Pset_Système de Référence Altimétrique_INFÉRIEUR, delta (P1) (cm) = IFC_Pset_Système de Référence Altimétrique_INFÉRIEUR, delta (P2) (cm) | IFC_Pset_Géométrie_P1 (POINT initial), Angle XY (deg) | IFC_Pset_Géométrie_P2 (POINT final), Hauteur (cm) | IFC_Pset_Géométrie_P2 (POINT final), Angle XY (deg) | IFC_Pset_Système de Référence Altimétrique_SUPÉRIEUR, NIVEAU | IFC_Pset_Système de Référence Altimétrique_SUPÉRIEUR, delta (cm) = IFC_Pset_Système de Référence Altimétrique_SUPÉRIEUR, delta (P1) (cm) = IFC_Pset_Système de Référence Altimétrique_SUPÉRIEUR, delta (P2) (cm) | sous Niveau | IFC_Pset_Système de Référence Altimétrique_INFÉRIEUR, NIVEAU | Longueur Pied (cm) | Longueur Tête (cm) | Hauteur Maximale (cm) | Hauteur Minimale (cm) | Surface en Plan (cm2) = Surface Pied (cm2) | Surface Tête (cm2) | Surface de la Paroi (cm2) | Volume (cm3) | Face gauche = Face droite = Face latérale | GrossVolume (cm3) | NetVolume (cm3) | NominalHeight (cm) | GrossFootprintArea (cm2) = NetFootprintArea (cm2) | GrossSideArea (cm2) | NetSideArea (cm2) | Group
Enveloppe 777991 | Rez-de-Jardin | 777991 | 1977773087 | 1 | 1 | 1130 | 02 | Rez-de-Jardin | no | rectangle | 167.804 | 262.4 | -1.94511e-11 | 0.500234 | 262.4 | 180.5 | HAUT Rez-de-Jardin (Rez-de-chaussée 1047) | -29 | <aucun> | Rez-de-Jardin (Rez-de-Jardin 15545) | 167.8 | 167.8 | 262.4 | 262.4 | 2000 | 2000 | 44000 | 530000 | Ivoire clair | 528382 | 528382 | 262.4 | 2013.65 | 44031.8 | 44031.8 | ...de stratigraphies = default; ...de matériaux et couleurs = Ivoire clair; ...de matériaux et couleurs - 1 = Ivoire clair; ...de matériaux et couleurs - 2 = Ivoire clair
Enveloppe 94636 | Niveau 1 | 94636 | 1977773087 | 1 | 0 | 0230 | 04 | Niveau 1 | no | rectangle | 292.306 | 376.102 | 0.0128504 | 179.898 | 376.102 | 359.898 | HAUT Niveau 1 (Niveau 2 13545) | 7.10543e-13 | <aucun> | Niveau 1 (Niveau 1 2343) | 292.3 | 292.3 | 376.1 | 376.1 | 3500 | 3500 | 109900 | 1320000 | Ivoire clair | 1319244 | 1319244 | 376.102 | 3507.67 | 109937 | 109937 | ...de stratigraphies = default; ...de matériaux et couleurs = Ivoire clair; ...de matériaux et couleurs - 1 = Ivoire clair; ...de matériaux et couleurs - 2 = Ivoire clair
Enveloppe 734961 | Niveau 2 | 734961 | 1977773087 | 1 | 1 | 1078 | 05 | Niveau 2 | no | rectangle | 266.273 | 245 | -1.95399e-11 | 179.841 | 245 | 359.841 | HAUT Niveau 2 (Mezzanine 49003) | 10 | <aucun> | Niveau 2 (Niveau 2 13545) | 266.3 | 266.3 | 245 | 245 | 3200 | 3200 | 65200 | 780000 | Ivoire clair | 782841 | 322589 | 245 | 3195.27 | 65236.8 | 26882.4 | ...de stratigraphies = default; ...de matériaux et couleurs = Ivoire clair; ...de matériaux et couleurs - 1 = Ivoire clair; ...de matériaux et couleurs - 2 = Ivoire clair
Enveloppe 2030007 | Mezzanine | 2030007 | -1156274542 | 0 | 1 | 1178 | 06 | Mezzanine | yes | rectangle | 22.7829 | 146.702 | 4.79616e-12 | 1.26484 | 146.702 | 181.265 | HAUT Mezzanine (Couverture 2134) | -133 | <aucun> | Mezzanine (Mezzanine 49003) | 22.8 | 22.8 | 146.7 | 146.7 | 300 | 300 | 3300 | 40000 | Chêne | 40107.7 | 40107.7 | 146.702 | 273.395 | 3342.31 | 3342.31 | ...de matériaux et couleurs = Chêne; ...de stratigraphies = default; ...de matériaux et couleurs - 1 = Chêne; ...de matériaux et couleurs - 2 = Chêne
Enveloppe 1888248 | Mezzanine | 1888248 | -1156274542 | 0 | 1 | 1173 | 06 | Mezzanine | no | trapèze | 189.562 | 183.006 | 48 | 91.3638 | 188.794 | 271.364 | Couverture (Couverture 2134) | 0 | Toit793923 | Mezzanine (Mezzanine 49003) | 189.6 | 189.7 | 188.8 | 183 | 2300 | 2300 | 35200 | 420000 | Chêne | 422675 | 422675 | 185.813 | 2274.74 | 35222.9 | 35222.9 | ...de matériaux et couleurs = Chêne; ...de stratigraphies = default; ...de matériaux et couleurs - 1 = Chêne; ...de matériaux et couleurs - 2 = Chêne
Enveloppe 197447 | Mezzanine | 197447 | -1156274542 | 0 | 1 | 0495 | 06 | Mezzanine | yes | rectangle | 372.532 | 132.005 | 48 | 0.769275 | 132.005 | 180.769 | HAUT Mezzanine (Couverture 2134) | -99.6977 | <aucun> | Mezzanine (Mezzanine 49003) | 372.5 | 372.5 | 132 | 132 | 4500 | 4500 | 49200 | 590000 | Chêne | 590112 | 590112 | 132.005 | 4470.38 | 49176 | 49176 | ...de matériaux et couleurs = Chêne; ...de stratigraphies = default; ...de matériaux et couleurs - 1 = Chêne; ...de matériaux et couleurs - 2 = Chêne
Enveloppe 198085 | Mezzanine | 198085 | -1156274542 | 1 | 1 | 0497 | 06 | Mezzanine | no | trapèze | 30.4179 | 295.745 | 1.06581e-12 | 1.36382 | 246.506 | 181.364 | Couverture (Couverture 2134) | 0 | Toit793923 | Mezzanine (Mezzanine 49003) | 30.4 | 57.8 | 295.7 | 246.5 | 400 | 700 | 8200 | 100000 | Chêne | 98964.7 | 98964.7 | 271.125 | 365.015 | 8247.06 | 8247.06 | ...de matériaux et couleurs = Chêne; ...de stratigraphies = default; ...de matériaux et couleurs - 1 = Chêne; ...de matériaux et couleurs - 2 = Chêne
Enveloppe 195708 | Mezzanine | 195708 | -1156274542 | 0 | 1 | 0486 | 06 | Mezzanine | yes | rectangle | 343.846 | 279.702 | 1.06581e-12 | 90.8667 | 279.702 | 270.867 | HAUT Mezzanine (Couverture 2134) | 7.10543e-13 | <aucun> | Mezzanine (Mezzanine 49003) | 343.8 | 343.8 | 279.7 | 279.7 | 4100 | 4100 | 96200 | 1150000 | Chêne | 1154095 | 564215 | 279.702 | 4126.15 | 96174.6 | 47017.9 | ...de matériaux et couleurs = Chêne; ...de stratigraphies = default; ...de matériaux et couleurs - 1 = Chêne; ...de matériaux et couleurs - 2 = Chêne
Enveloppe 195761 | Mezzanine | 195761 | -1156274542 | 0 | 1 | 0487 | 06 | Mezzanine | no | rectangle | 337.438 | 186.702 | 48 | 91.3638 | 186.702 | 271.364 | HAUT Mezzanine (Couverture 2134) | -45 | <aucun> | Mezzanine (Mezzanine 49003) | 337.4 | 337.4 | 186.7 | 186.7 | 4000 | 4000 | 63000 | 760000 | Chêne | 756007 | 756007 | 186.702 | 4049.26 | 63000.6 | 63000.6 | ...de matériaux et couleurs = Chêne; ...de stratigraphies = default; ...de matériaux et couleurs - 1 = Chêne; ...de matériaux et couleurs - 2 = Chêne
Enveloppe 195886 | Mezzanine | 195886 | -1156274542 | 1 | 1 | 0488 | 06 | Mezzanine | yes | rectangle | 549.883 | 134.702 | 48 | 91.0959 | 134.702 | 271.096 | HAUT Mezzanine (Couverture 2134) | -97 | <aucun> | Mezzanine (Mezzanine 49003) | 549.9 | 549.9 | 134.7 | 134.7 | 6600 | 6600 | 74100 | 890000 | Chêne | 888847 | 888847 | 134.702 | 6598.6 | 74070.6 | 74070.6 | ...de matériaux et couleurs = Chêne; ...de stratigraphies = default; ...de matériaux et couleurs - 1 = Chêne; ...de matériaux et couleurs - 2 = Chêne
Enveloppe 201482 | Mezzanine | 201482 | -1156274542 | 1 | 1 | 0506 | 06 | Mezzanine | no | trapèze | 49.4199 | 50 | 4.79616e-12 | 0.406632 | 50 | 180.407 | HAUT Mezzanine (Couverture 2134) | -229.702 | <aucun> | Mezzanine (Mezzanine 49003) | 49.4 | 49.4 | 50 | 50 | 600 | 600 | 2500 | 30000 | Chêne | 29652 | 29652 | 50 | 593.039 | 2471 | 2471 | ...de matériaux et couleurs = Chêne; ...de stratigraphies = default; ...de matériaux et couleurs - 1 = Chêne; ...de matériaux et couleurs - 2 = Chêne

# IfcWallStandardCase: default 135, Enveloppe 134326
In: Rez-de-Jardin
Type - Material: <aucun> 13.5 cm
Description: Enveloppe; Group: ...de stratigraphies = default; ...de matériaux et couleurs = Ivoire clair; ...de matériaux et couleurs - 1 = Ivoire clair; ...de matériaux et couleurs - 2 = Ivoire clair
__RECOGNIZE__ - ID: 134326; TPLG: 366; TPLG_OD: 9000; GENERATE: 1
CTLG_EXTERNAL_LINK - 0, DocType: 2; 0, Tag: 0; 0, Crc: 1977773087; 1, DocType: 2; 1, Tag: 100; 1, Crc: 1977773087; 2, DocType: 2; 2, Tag: 200; 2, Crc: 1977773087; 3, DocType: 9; 3, Tag: 0; 3, Crc: 1440187461
IFC_PSET_PolygonOffset - polygonOffsetFactor: 2; polygonOffsetUnits: 2
IFC_Pset_Alignment - Alignment: 1
IFC_Pset_Strat_Detail_Align - ExternalFace: 0
IFC_Pset_Caractéristiques - ID: 134326; Numérotation: 0309; Numéro niveau: 02; Titre niveau: Rez-de-Jardin; Stratigraphie: default [135,00]; Épaisseur: 13.5 cm; Épaisseur VARIABLE: yes
IFC_Pset_Caractéristiques_FRUIT - Fruit: no; Taille: 0 cm
IFC_Pset_Géométrie - Forme en Élévation: trapèze; Longueur: 89.0001 cm; Hauteur: 132.796 cm; Cote: 0 cm
IFC_Pset_Géométrie_P1 (POINT initial) - Hauteur: 132.796 cm; Cote: 0 cm; Angle XY: 163.922 deg
IFC_Pset_Géométrie_P2 (POINT final) - Hauteur: 78.9927 cm; Cote: 0 cm; Angle XY: 343.922 deg
IFC_Pset_Système de Référence Altimétrique_SUPÉRIEUR - NIVEAU: HAUT Rez-de-Jardin (Rez-de-chaussée 1047); delta: 0 cm; delta (P1): 0 cm; delta (P2): 0 cm; sous Niveau: <aucun>
IFC_Pset_Système de Référence Altimétrique_INFÉRIEUR - NIVEAU: Rez-de-Jardin (Rez-de-Jardin 15545); delta: 0 cm; delta (P1): 0 cm; delta (P2): 0 cm; sous Niveau: extérieur
IFC_Pset_Données Métré - Longueur Pied: 89 cm; Longueur Tête: 104 cm; Hauteur Maximale: 132.8 cm; Hauteur Minimale: 79 cm; Surface en Plan: 1300 cm2; Surface Pied: 1300 cm2; Surface Tête: 1500 cm2; Surface de la Paroi: 9400 cm2; Volume: 130000 cm3
IFC_Pset_Matériaux - Face gauche: Ivoire clair; Face droite: Ivoire clair; Face latérale: Ivoire clair
Pset_WallCommon - Reference: default [135,00] (..\VERTICALES\Default\)
BaseQuantities - GrossVolume: 136116 cm3; NetVolume: 136116 cm3; NominalLength: 89.0001 cm; NominalWidth: 14.4426 cm; NominalHeight: 105.894 cm; GrossFootprintArea: 1285.39 cm2; NetFootprintArea: 1285.39 cm2; GrossSideArea: 9424.61 cm2; NetSideArea: 9424.61 cm2

# IfcWallStandardCase: default 140 (2)
In: Niveau 2
Type - Material: <aucun> 14 cm
Description: Enveloppe; Group: ...de stratigraphies = default; ...de matériaux et couleurs = Ivoire clair; ...de matériaux et couleurs - 1 = Ivoire clair; ...de matériaux et couleurs - 2 = Ivoire clair
__RECOGNIZE__ - TPLG: 366; TPLG_OD: 9000; GENERATE: 1
CTLG_EXTERNAL_LINK - 0, DocType: 2; 0, Tag: 0; 0, Crc: 1977773087; 1, DocType: 2; 1, Tag: 100; 1, Crc: 1977773087; 2, DocType: 2; 2, Tag: 200; 2, Crc: 1977773087; 3, DocType: 9; 3, Tag: 0; 3, Crc: -106377247
IFC_PSET_PolygonOffset - polygonOffsetFactor: 2; polygonOffsetUnits: 2
IFC_Pset_Alignment - Alignment: 1
IFC_Pset_Strat_Detail_Align - ExternalFace: 1
IFC_Pset_Caractéristiques - Numéro niveau: 05; Titre niveau: Niveau 2; Stratigraphie: default [140,00]; Épaisseur: 14 cm; Épaisseur VARIABLE: no
IFC_Pset_Caractéristiques_FRUIT - Fruit: no; Taille: 0 cm
IFC_Pset_Géométrie - Forme en Élévation: rectangle; Cote: -1.95399e-11 cm
IFC_Pset_Géométrie_P1 (POINT initial) - Cote: -1.95399e-11 cm; Angle XY: 179.869 deg
IFC_Pset_Géométrie_P2 (POINT final) - Cote: -1.95399e-11 cm; Angle XY: 359.869 deg
IFC_Pset_Système de Référence Altimétrique_SUPÉRIEUR - NIVEAU: HAUT Niveau 2 (Mezzanine 49003); sous Niveau: <aucun>
IFC_Pset_Système de Référence Altimétrique_INFÉRIEUR - NIVEAU: Niveau 2 (Niveau 2 13545); delta: -1.95399e-11 cm; delta (P1): -1.95399e-11 cm; delta (P2): -1.95399e-11 cm; sous Niveau: <aucun>
IFC_Pset_Matériaux - Face gauche: Ivoire clair; Face droite: Ivoire clair; Face latérale: Ivoire clair
Pset_WallCommon - Reference: default [140,00] (..\VERTICALES\Default\)
BaseQuantities - NominalWidth: 14 cm
Name | __RECOGNIZE__, ID = IFC_Pset_Caractéristiques, ID | Numérotation | Longueur (cm) = NominalLength (cm) | IFC_Pset_Géométrie, Hauteur (cm) = IFC_Pset_Géométrie_P1 (POINT initial), Hauteur (cm) = IFC_Pset_Géométrie_P2 (POINT final), Hauteur (cm) = Hauteur Maximale (cm) = Hauteur Minimale (cm) = NominalHeight (cm) | delta (cm) = delta (P1) (cm) = delta (P2) (cm) | Longueur Pied (cm) = Longueur Tête (cm) | Surface en Plan (cm2) = Surface Pied (cm2) = Surface Tête (cm2) | Surface de la Paroi (cm2) | Volume (cm3) | GrossVolume (cm3) | NetVolume (cm3) | GrossFootprintArea (cm2) = NetFootprintArea (cm2) | GrossSideArea (cm2) | NetSideArea (cm2)
Enveloppe 740281 | 740281 | 1083 | 223.932 | 240 | 5 | 223.9 | 3100 | 53700 | 750000 | 752410 | 382541 | 3135.04 | 53743.6 | 27324.4
Enveloppe 740525 | 740525 | 1084 | 147.689 | 235 | 8.34888e-12 | 147.7 | 2100 | 34700 | 490000 | 485896 | 336079 | 2067.64 | 34706.9 | 24005.7

# IfcWallStandardCase: default 145 (3)
In: Rez-de-Jardin
Type - Material: <aucun> 14.5 cm
Description: Enveloppe; Group: ...de stratigraphies = default; ...de matériaux et couleurs = Ivoire clair; ...de matériaux et couleurs - 1 = Ivoire clair; ...de matériaux et couleurs - 2 = Ivoire clair
__RECOGNIZE__ - TPLG: 366; TPLG_OD: 9000; GENERATE: 1
CTLG_EXTERNAL_LINK - 0, DocType: 2; 0, Tag: 0; 0, Crc: 1977773087; 1, DocType: 2; 1, Tag: 100; 1, Crc: 1977773087; 2, DocType: 2; 2, Tag: 200; 2, Crc: 1977773087; 3, DocType: 9; 3, Tag: 0; 3, Crc: -319058736
IFC_PSET_PolygonOffset - polygonOffsetFactor: 2; polygonOffsetUnits: 2
IFC_Pset_Strat_Detail_Align - ExternalFace: 0
IFC_Pset_Caractéristiques - Numéro niveau: 02; Titre niveau: Rez-de-Jardin; Stratigraphie: default [145,00]; Épaisseur: 14.5 cm
IFC_Pset_Caractéristiques_FRUIT - Fruit: no; Taille: 0 cm
IFC_Pset_Géométrie - Forme en Élévation: rectangle; Hauteur: 166.4 cm
IFC_Pset_Géométrie_P1 (POINT initial) - Hauteur: 166.4 cm
IFC_Pset_Géométrie_P2 (POINT final) - Hauteur: 166.4 cm
IFC_Pset_Système de Référence Altimétrique_SUPÉRIEUR - NIVEAU: HAUT Rez-de-Jardin (Rez-de-chaussée 1047); delta: -175 cm; delta (P1): -175 cm; delta (P2): -175 cm; sous Niveau: <aucun>
IFC_Pset_Système de Référence Altimétrique_INFÉRIEUR - NIVEAU: Rez-de-Jardin (Rez-de-Jardin 15545); sous Niveau: extérieur
IFC_Pset_Données Métré - Hauteur Maximale: 166.4 cm; Hauteur Minimale: 166.4 cm
IFC_Pset_Matériaux - Face gauche: Ivoire clair; Face droite: Ivoire clair; Face latérale: Ivoire clair
Pset_WallCommon - Reference: default [145,00] (..\VERTICALES\Default\)
BaseQuantities - NominalHeight: 166.4 cm
Name | __RECOGNIZE__, ID = IFC_Pset_Caractéristiques, ID | Alignment | Numérotation | Épaisseur VARIABLE | Longueur (cm) = NominalLength (cm) | IFC_Pset_Géométrie, Cote (cm) = IFC_Pset_Géométrie_P1 (POINT initial), Cote (cm) = IFC_Pset_Géométrie_P2 (POINT final), Cote (cm) = delta (cm) = delta (P1) (cm) = delta (P2) (cm) | IFC_Pset_Géométrie_P1 (POINT initial), Angle XY (deg) | IFC_Pset_Géométrie_P2 (POINT final), Angle XY (deg) | Longueur Pied (cm) = Longueur Tête (cm) | Surface en Plan (cm2) = Surface Pied (cm2) = Surface Tête (cm2) | Surface de la Paroi (cm2) | Volume (cm3) | GrossVolume (cm3) = NetVolume (cm3) | NominalWidth (cm) | GrossFootprintArea (cm2) = NetFootprintArea (cm2) | GrossSideArea (cm2) = NetSideArea (cm2)
Enveloppe 146329 | 146329 | 1 | 0317 | no | 36.9322 | 1.33227e-13 | 166.455 | 346.455 | 36.9 | 600 | 6100 | 90000 | 89110.3 | 14.5 | 535.517 | 6145.54
Enveloppe 149510 | 149510 | 0 | 0318 | no | 109.249 | 0 | 165.254 | 345.254 | 109.2 | 1600 | 18200 | 270000 | 263597 | 14.5 | 1584.11 | 18179.1
Enveloppe 145146 | 145146 | 1 | 0316 | yes | 88.6689 | 1.33227e-13 | 164.74 | 344.74 | 88.7 | 1400 | 14800 | 220000 | 225858 | 15.3077 | 1357.32 | 14754.5

# IfcWallStandardCase: default 146 (2)
In: Rez-de-Jardin
Type - Material: <aucun> 14.6 cm
Description: Enveloppe; Group: ...de stratigraphies = default; ...de matériaux et couleurs = Ivoire clair; ...de matériaux et couleurs - 1 = Ivoire clair; ...de matériaux et couleurs - 2 = Ivoire clair
__RECOGNIZE__ - TPLG: 366; TPLG_OD: 9000; GENERATE: 1
CTLG_EXTERNAL_LINK - 0, DocType: 2; 0, Tag: 0; 0, Crc: 1977773087; 1, DocType: 2; 1, Tag: 100; 1, Crc: 1977773087; 2, DocType: 2; 2, Tag: 200; 2, Crc: 1977773087; 3, DocType: 9; 3, Tag: 0; 3, Crc: -1036328
IFC_PSET_PolygonOffset - polygonOffsetFactor: 2; polygonOffsetUnits: 2
IFC_Pset_Alignment - Alignment: 1
IFC_Pset_Strat_Detail_Align - ExternalFace: 1
IFC_Pset_Caractéristiques - Numéro niveau: 02; Titre niveau: Rez-de-Jardin; Stratigraphie: default [146,00]; Épaisseur: 14.6 cm; Épaisseur VARIABLE: no
IFC_Pset_Caractéristiques_FRUIT - Fruit: no; Taille: 0 cm
IFC_Pset_Géométrie - Forme en Élévation: trapèze; Cote: -1.94511e-11 cm
IFC_Pset_Géométrie_P1 (POINT initial) - Cote: -1.94511e-11 cm
IFC_Pset_Géométrie_P2 (POINT final) - Cote: -1.94511e-11 cm
IFC_Pset_Système de Référence Altimétrique_SUPÉRIEUR - NIVEAU: HAUT Rez-de-Jardin (Rez-de-chaussée 1047); sous Niveau: <aucun>
IFC_Pset_Système de Référence Altimétrique_INFÉRIEUR - NIVEAU: Rez-de-Jardin (Rez-de-Jardin 15545); delta: -1.94511e-11 cm; delta (P1): -1.94511e-11 cm; delta (P2): -1.94511e-11 cm; sous Niveau: <aucun>
IFC_Pset_Matériaux - Face gauche: Ivoire clair; Face droite: Ivoire clair; Face latérale: Ivoire clair
Pset_WallCommon - Reference: default [146,00] (..\VERTICALES\Default\)
BaseQuantities - NominalWidth: 14.6 cm
Name | __RECOGNIZE__, ID = IFC_Pset_Caractéristiques, ID | Numérotation | Longueur (cm) = NominalLength (cm) | IFC_Pset_Géométrie, Hauteur (cm) | IFC_Pset_Géométrie_P1 (POINT initial), Hauteur (cm) = Hauteur Maximale (cm) | IFC_Pset_Géométrie_P1 (POINT initial), Angle XY (deg) | IFC_Pset_Géométrie_P2 (POINT final), Hauteur (cm) | IFC_Pset_Géométrie_P2 (POINT final), Angle XY (deg) | delta (cm) = delta (P1) (cm) | delta (P2) (cm) | Longueur Pied (cm) | Longueur Tête (cm) | Hauteur Minimale (cm) | Surface en Plan (cm2) = Surface Pied (cm2) | Surface Tête (cm2) | Surface de la Paroi (cm2) | Volume (cm3) | GrossVolume (cm3) = NetVolume (cm3) | NominalHeight (cm) | GrossFootprintArea (cm2) = NetFootprintArea (cm2) | GrossSideArea (cm2) = NetSideArea (cm2)
Enveloppe 266795 | 266795 | 0530 | 91.1614 | 72.5 | 80 | 179.665 | 32 | 359.665 | -226.4 | -259.4 | 91.2 | 103.1 | 32 | 1300 | 1600 | 5100 | 80000 | 74663.9 | 56.0979 | 1330.96 | 5113.96
Enveloppe 247715 | 247715 | 0526 | 105.021 | 74.5 | 82 | 178.697 | 31.6963 | 358.697 | 0 | 0 | 105 | 116.4 | 31.7 | 1500 | 1700 | 6700 | 100000 | 93340.5 | 60.8753 | 1533.31 | 6393.18

# IfcWallStandardCase: default 148, Enveloppe 258965
In: Rez-de-Jardin
Type - Material: <aucun> 14.8 cm
Description: Enveloppe; Group: ...de stratigraphies = default; ...de matériaux et couleurs = Ivoire clair; ...de matériaux et couleurs - 1 = Ivoire clair; ...de matériaux et couleurs - 2 = Ivoire clair
__RECOGNIZE__ - ID: 258965; TPLG: 366; TPLG_OD: 9000; GENERATE: 1
CTLG_EXTERNAL_LINK - 0, DocType: 2; 0, Tag: 0; 0, Crc: 1977773087; 1, DocType: 2; 1, Tag: 100; 1, Crc: 1977773087; 2, DocType: 2; 2, Tag: 200; 2, Crc: 1977773087; 3, DocType: 9; 3, Tag: 0; 3, Crc: -1309936700
IFC_PSET_PolygonOffset - polygonOffsetFactor: 2; polygonOffsetUnits: 2
IFC_Pset_Alignment - Alignment: 0
IFC_Pset_Strat_Detail_Align - ExternalFace: 1
IFC_Pset_Caractéristiques - ID: 258965; Numérotation: 0528; Numéro niveau: 02; Titre niveau: Rez-de-Jardin; Stratigraphie: default [148,00]; Épaisseur: 14.8 cm; Épaisseur VARIABLE: no
IFC_Pset_Caractéristiques_FRUIT - Fruit: no; Taille: 0 cm
IFC_Pset_Géométrie - Forme en Élévation: rectangle; Longueur: 107.708 cm; Hauteur: 114.5 cm; Cote: -1.94511e-11 cm
IFC_Pset_Géométrie_P1 (POINT initial) - Hauteur: 114.5 cm; Cote: -1.94511e-11 cm; Angle XY: 178.697 deg
IFC_Pset_Géométrie_P2 (POINT final) - Hauteur: 114.5 cm; Cote: -1.94511e-11 cm; Angle XY: 358.697 deg
IFC_Pset_Système de Référence Altimétrique_SUPÉRIEUR - NIVEAU: HAUT Rez-de-Jardin (Rez-de-chaussée 1047); delta: -176.9 cm; delta (P1): -176.9 cm; delta (P2): -176.9 cm; sous Niveau: <aucun>
IFC_Pset_Système de Référence Altimétrique_INFÉRIEUR - NIVEAU: Rez-de-Jardin (Rez-de-Jardin 15545); delta: -1.94511e-11 cm; delta (P1): -1.94511e-11 cm; delta (P2): -1.94511e-11 cm; sous Niveau: <aucun>
IFC_Pset_Données Métré - Longueur Pied: 107.7 cm; Longueur Tête: 107.7 cm; Hauteur Maximale: 114.5 cm; Hauteur Minimale: 114.5 cm; Surface en Plan: 1600 cm2; Surface Pied: 1600 cm2; Surface Tête: 1600 cm2; Surface de la Paroi: 12300 cm2; Volume: 180000 cm3
IFC_Pset_Matériaux - Face gauche: Ivoire clair; Face droite: Ivoire clair; Face latérale: Ivoire clair
Pset_WallCommon - Reference: default [148,00] (..\VERTICALES\Default\)
BaseQuantities - GrossVolume: 182522 cm3; NetVolume: 182522 cm3; NominalLength: 107.708 cm; NominalWidth: 14.8 cm; NominalHeight: 114.5 cm; GrossFootprintArea: 1594.08 cm2; NetFootprintArea: 1594.08 cm2; GrossSideArea: 12332.6 cm2; NetSideArea: 12332.6 cm2

# IfcWallStandardCase: default 150 (112)
Type - Material: <aucun> 15 cm
__RECOGNIZE__ - GENERATE: 1
CTLG_EXTERNAL_LINK - 0, DocType: 2; 0, Tag: 0; 1, DocType: 2; 1, Tag: 100; 2, DocType: 2; 2, Tag: 200; 3, DocType: 9; 3, Tag: 0; 3, Crc: 1656458995
IFC_PSET_PolygonOffset - polygonOffsetFactor: 2; polygonOffsetUnits: 2
IFC_Pset_Caractéristiques - Stratigraphie: default [150,00]; Épaisseur: 15 cm
IFC_Pset_Caractéristiques_FRUIT - Fruit: no; Taille: 0 cm
IFC_Pset_Système de Référence Altimétrique_INFÉRIEUR - sous Niveau: <aucun>
Pset_WallCommon - Reference: default [150,00] (..\VERTICALES\Default\)
Name | In | Description | __RECOGNIZE__, ID = IFC_Pset_Caractéristiques, ID | TPLG | TPLG_OD | 0, Crc | 1, Crc = 2, Crc | Alignment | ExternalFace | Numérotation | Numéro niveau | Titre niveau | Épaisseur VARIABLE | Forme en Élévation | Longueur (cm) = NominalLength (cm) | IFC_Pset_Géométrie, Hauteur (cm) = IFC_Pset_Géométrie_P1 (POINT initial), Hauteur (cm) | IFC_Pset_Géométrie, Cote (cm) = IFC_Pset_Géométrie_P1 (POINT initial), Cote (cm) = IFC_Pset_Géométrie_P2 (POINT final), Cote (cm) = IFC_Pset_Système de Référence Altimétrique_INFÉRIEUR, delta (cm) = IFC_Pset_Système de Référence Altimétrique_INFÉRIEUR, delta (P1) (cm) = IFC_Pset_Système de Référence Altimétrique_INFÉRIEUR, delta (P2) (cm) | IFC_Pset_Géométrie_P1 (POINT initial), Angle XY (deg) | IFC_Pset_Géométrie_P2 (POINT final), Hauteur (cm) | IFC_Pset_Géométrie_P2 (POINT final), Angle XY (deg) | IFC_Pset_Système de Référence Altimétrique_SUPÉRIEUR, NIVEAU | IFC_Pset_Système de Référence Altimétrique_SUPÉRIEUR, delta (cm) = IFC_Pset_Système de Référence Altimétrique_SUPÉRIEUR, delta (P1) (cm) = IFC_Pset_Système de Référence Altimétrique_SUPÉRIEUR, delta (P2) (cm) | sous Niveau | IFC_Pset_Système de Référence Altimétrique_INFÉRIEUR, NIVEAU | Longueur Pied (cm) | Longueur Tête (cm) | Hauteur Maximale (cm) | Hauteur Minimale (cm) | Surface en Plan (cm2) | Surface Pied (cm2) | Surface Tête (cm2) | Surface de la Paroi (cm2) | Volume (cm3) | Face gauche | Face droite = Face latérale | GrossVolume (cm3) | NetVolume (cm3) | NominalWidth (cm) | NominalHeight (cm) | GrossFootprintArea (cm2) = NetFootprintArea (cm2) | GrossSideArea (cm2) | NetSideArea (cm2) | Group
Enveloppe 71394 | Rez-de-Jardin | Enveloppe | 71394 | 366 | 9000 | 1977773087 | 1977773087 | 1 | 0 | 0149 | 02 | Rez-de-Jardin | yes | rectangle | 207.211 | 291.413 | -1.94511e-11 | 45.3123 | 291.413 | 225.312 | HAUT Rez-de-Jardin (Rez-de-chaussée 1047) | 0.0128504 | <aucun> | Rez-de-Jardin (Rez-de-Jardin 15545) | 207.2 | 207.2 | 291.4 | 291.4 | 3100 | 3100 | 3100 | 60400 | 910000 | Ivoire clair | Ivoire clair | 905759 | 905759 | 15 | 291.413 | 3108.16 | 60383.9 | 60383.9 | ...de stratigraphies = default; ...de matériaux et couleurs = Ivoire clair; ...de matériaux et couleurs - 1 = Ivoire clair; ...de matériaux et couleurs - 2 = Ivoire clair
Enveloppe 92070 | Rez-de-Jardin | Enveloppe | 92070 | 366 | 9000 | 1977773087 | 1977773087 | 0 | 0 | 0179 | 02 | Rez-de-Jardin | no | rectangle | 332.406 | 157.9 | -1.94511e-11 | 89.8313 | 157.9 | 269.831 | HAUT Rez-de-Jardin (Rez-de-chaussée 1047) | -133.5 | <aucun> | Rez-de-Jardin (Rez-de-Jardin 15545) | 332.4 | 332.4 | 157.9 | 157.9 | 5000 | 5000 | 5000 | 52500 | 790000 | Ivoire clair | Ivoire clair | 787306 | 787306 | 15 | 157.9 | 4986.1 | 52487.1 | 52487.1 | ...de stratigraphies = default; ...de matériaux et couleurs = Ivoire clair; ...de matériaux et couleurs - 1 = Ivoire clair; ...de matériaux et couleurs - 2 = Ivoire clair
Enveloppe 78761 | Rez-de-Jardin | Enveloppe | 78761 | 366 | 9000 | 1977773087 | 1977773087 | 1 | 0 | 0177 | 02 | Rez-de-Jardin | no | trapèze | 140.221 | 199.095 | -1.94511e-11 | 0.0141066 | 258.41 | 180.014 | HAUT Rez-de-Jardin (Rez-de-chaussée 1047) | 0 | <aucun> | Rez-de-Jardin (Rez-de-Jardin 15545) | 140.2 | 152.2 | 258.4 | 199.1 | 2100 | 2100 | 2300 | 33200 | 500000 | Ivoire clair | Ivoire clair | 498217 | 498217 | 15 | 236.872 | 2103.32 | 33214.5 | 33214.5 | ...de stratigraphies = default; ...de matériaux et couleurs = Ivoire clair; ...de matériaux et couleurs - 1 = Ivoire clair; ...de matériaux et couleurs - 2 = Ivoire clair
Enveloppe 92111 | Rez-de-Jardin | Enveloppe | 92111 | 366 | 9000 | 1977773087 | 1977773087 | 0 | 0 | 0180 | 02 | Rez-de-Jardin | no | rectangle | 330.936 | 157.9 | -1.94511e-11 | 89.5501 | 157.9 | 269.55 | HAUT Rez-de-Jardin (Rez-de-chaussée 1047) | -133.5 | <aucun> | Rez-de-Jardin (Rez-de-Jardin 15545) | 330.9 | 330.9 | 157.9 | 157.9 | 5000 | 5000 | 5000 | 52200 | 780000 | Ivoire clair | Ivoire clair | 783824 | 783824 | 15 | 157.9 | 4964.04 | 52254.9 | 52254.9 | ...de stratigraphies = default; ...de matériaux et couleurs = Ivoire clair; ...de matériaux et couleurs - 1 = Ivoire clair; ...de matériaux et couleurs - 2 = Ivoire clair
Enveloppe 64484 | Rez-de-Jardin | Enveloppe | 64484 | 366 | 9000 | 1977773087 | 1977773087 | 1 | 0 | 0114 | 02 | Rez-de-Jardin | no | rectangle | 152.351 | 291.413 | -1.94511e-11 | 90.2011 | 291.413 | 270.201 | HAUT Rez-de-Jardin (Rez-de-chaussée 1047) | 0.0128504 | <aucun> | Rez-de-Jardin (Rez-de-Jardin 15545) | 152.4 | 152.4 | 291.4 | 291.4 | 2300 | 2300 | 2300 | 44400 | 670000 | Ivoire clair | Ivoire clair | 665956 | 665956 | 15 | 291.413 | 2285.26 | 44397.1 | 44397.1 | ...de stratigraphies = default; ...de matériaux et couleurs = Ivoire clair; ...de matériaux et couleurs - 1 = Ivoire clair; ...de matériaux et couleurs - 2 = Ivoire clair
Enveloppe 52893 | Rez-de-Jardin | Enveloppe | 52893 | 366 | 9000 | 1977773087 | 1977773087 | 1 | 0 | 0077 | 02 | Rez-de-Jardin | no | rectangle | 139.432 | 291.413 | -1.94511e-11 | 90.2011 | 291.413 | 270.201 | HAUT Rez-de-Jardin (Rez-de-chaussée 1047) | 0.0128504 | <aucun> | Rez-de-Jardin (Rez-de-Jardin 15545) | 139.4 | 139.4 | 291.4 | 291.4 | 2100 | 2100 | 2100 | 40600 | 610000 | Ivoire clair | Ivoire clair | 609487 | 609487 | 15 | 291.413 | 2091.49 | 40632.5 | 40632.5 | ...de stratigraphies = default; ...de matériaux et couleurs = Ivoire clair; ...de matériaux et couleurs - 1 = Ivoire clair; ...de matériaux et couleurs - 2 = Ivoire clair
Enveloppe 52934 | Rez-de-Jardin | Enveloppe | 52934 | 366 | 9000 | 1977773087 | 1977773087 | 0 | 0 | 0079 | 02 | Rez-de-Jardin | no | trapèze | 84.4199 | 230.24 | -1.94511e-11 | 0.575325 | 260.4 | 180.575 | HAUT Rez-de-Jardin (Rez-de-chaussée 1047) | 0 | <aucun> | Rez-de-Jardin (Rez-de-Jardin 15545) | 84.4 | 89.6 | 260.4 | 230.2 | 1300 | 1300 | 1400 | 21300 | 320000 | Ivoire clair | Ivoire clair | 319198 | 319198 | 15 | 252.072 | 1266.3 | 21279.9 | 21279.9 | ...de stratigraphies = default; ...de matériaux et couleurs = Ivoire clair; ...de matériaux et couleurs - 1 = Ivoire clair; ...de matériaux et couleurs - 2 = Ivoire clair
Enveloppe 263538 | Rez-de-Jardin | Enveloppe | 263538 | 366 | 9000 | 1977773087 | 1977773087 | 0 | 1 | 0529 | 02 | Rez-de-Jardin | no | rectangle | 108.775 | 114.5 | -1.94511e-11 | 178.345 | 114.5 | 358.345 | HAUT Rez-de-Jardin (Rez-de-chaussée 1047) | -176.9 | <aucun> | Rez-de-Jardin (Rez-de-Jardin 15545) | 108.8 | 108.8 | 114.5 | 114.5 | 1600 | 1600 | 1600 | 12500 | 190000 | Ivoire clair | Ivoire clair | 186821 | 186821 | 15 | 114.5 | 1631.62 | 12454.7 | 12454.7 | ...de stratigraphies = default; ...de matériaux et couleurs = Ivoire clair; ...de matériaux et couleurs - 1 = Ivoire clair; ...de matériaux et couleurs - 2 = Ivoire clair
Enveloppe 294982 | Rez-de-Jardin | Enveloppe | 294982 | 366 | 9000 | 1977773087 | 1977773087 | 0 | 0 | 0533 | 02 | Rez-de-Jardin | no | rectangle | 71.1198 | 156.4 | 8.88178e-14 | 146.74 | 156.4 | 326.74 | HAUT Rez-de-Jardin (Rez-de-chaussée 1047) | -135 | <aucun> | Rez-de-Jardin (Rez-de-Jardin 15545) | 71.1 | 71.1 | 156.4 | 156.4 | 1100 | 1100 | 1100 | 11100 | 170000 | Ivoire clair | Ivoire clair | 166847 | 166847 | 15 | 156.4 | 1066.8 | 11123.2 | 11123.2 | ...de stratigraphies = default; ...de matériaux et couleurs = Ivoire clair; ...de matériaux et couleurs - 1 = Ivoire clair; ...de matériaux et couleurs - 2 = Ivoire clair
Enveloppe courbe 278754 | Rez-de-Jardin | Enveloppe courbe | 278754 | 367 | 9001 | -746779066 | -746779066 | 0 | 0 | 32 | 02 | Rez-de-Jardin | no | rectangle | 268.902 | 111 | 43.7 | 50.4212 | 111 | 230.421 | HAUT Rez-de-Jardin (Rez-de-chaussée 1047) | -136.7 | <aucun> | Rez-de-Jardin (Rez-de-Jardin 15545) | 268.9 | 268.9 | 111 | 111 | 2600 | 4000 | 4000 | 29900 | 450000 | Blanc | Blanc | 446773 | 446773 | 14.9682 | 111 | 4024.98 | 29848.1 | 29848.1 | ...de matériaux et couleurs = Blanc; ...de matériaux et couleurs - 1 = Blanc; ...de matériaux et couleurs - 2 = Blanc; ...de stratigraphies = default | IFC_Pset_Géométrie - Rayon: 305.565 cm; Point arc: [1 367,4; -1 953,1] cm; Centre: [1 361,5; -1 655,1] cm; Angle de la Tangente: 20.9214 deg
Enveloppe courbe 263823 | Rez-de-Jardin | Enveloppe courbe | 263823 | 367 | 9001 | -746779066 | -746779066 | 0 | 0 | 31 | 02 | Rez-de-Jardin | no | rectangle | 325.483 | 111 | 43.7 | 62.9174 | 111 | 242.917 | HAUT Rez-de-Jardin (Rez-de-chaussée 1047) | -136.7 | <aucun> | Rez-de-Jardin (Rez-de-Jardin 15545) | 325.5 | 325.5 | 111 | 111 | 3100 | 4900 | 4900 | 36100 | 540000 | Blanc | Blanc | 540760 | 540760 | 14.9676 | 111 | 4871.71 | 36128.6 | 36128.6 | ...de matériaux et couleurs = Blanc; ...de matériaux et couleurs - 1 = Blanc; ...de matériaux et couleurs - 2 = Blanc; ...de stratigraphies = default | IFC_Pset_Géométrie - Rayon: 296.401 cm; Point arc: [1 611,8; -1 810,9] cm; Centre: [1 362,4; -1 665,0] cm; Angle de la Tangente: 27.1696 deg
Enveloppe courbe 244730 | Rez-de-Jardin | Enveloppe courbe | 244730 | 367 | 9001 | -746779066 | -746779066 | 0 | 0 | 30 | 02 | Rez-de-Jardin | no | rectangle | 331.199 | 112 | 43.7 | 65.0967 | 112 | 245.097 | HAUT Rez-de-Jardin (Rez-de-chaussée 1047) | -135.7 | <aucun> | Rez-de-Jardin (Rez-de-Jardin 15545) | 331.2 | 331.2 | 112 | 112 | 3200 | 5000 | 5000 | 37100 | 560000 | Blanc | Blanc | 555168 | 555168 | 14.9664 | 112 | 4956.86 | 37094.3 | 37094.3 | ...de matériaux et couleurs = Blanc; ...de matériaux et couleurs - 1 = Blanc; ...de matériaux et couleurs - 2 = Blanc; ...de stratigraphies = default | IFC_Pset_Géométrie - Rayon: 291.51 cm; Point arc: [1 594,3; -1 211,4] cm; Centre: [1 363,2; -1 376,6] cm; Angle de la Tangente: 28.2592 deg
Enveloppe courbe 292679 | Rez-de-Jardin | Enveloppe courbe | 292679 | 367 | 9001 | -746779066 | -746779066 | 1 | 0 | 41 | 02 | Rez-de-Jardin | no | rectangle | 85.9872 | 111 | 43.7 | 14.4165 | 111 | 194.416 | HAUT Rez-de-Jardin (Rez-de-chaussée 1047) | -136.7 | <aucun> | Rez-de-Jardin (Rez-de-Jardin 15545) | 86 | 86 | 111 | 111 | 800 | 1300 | 1300 | 9500 | 140000 | Blanc | Blanc | 142960 | 142960 | 14.9781 | 111 | 1287.93 | 9544.58 | 9544.58 | ...de matériaux et couleurs = Blanc; ...de matériaux et couleurs - 1 = Blanc; ...de matériaux et couleurs - 2 = Blanc; ...de stratigraphies = default | IFC_Pset_Géométrie - Rayon: 341.741 cm; Point arc: [1 319,6; -938,0] cm; Centre: [1 631,6; -817,9] cm; Angle de la Tangente: 2.91908 deg
Enveloppe courbe 292967 | Rez-de-Jardin | Enveloppe courbe | 292967 | 367 | 9001 | -746779066 | -746779066 | 1 | 0 | 42 | 02 | Rez-de-Jardin | no | rectangle | 196.867 | 111 | 43.7 | 40.5795 | 111 | 220.579 | HAUT Rez-de-Jardin (Rez-de-chaussée 1047) | -136.7 | <aucun> | Rez-de-Jardin (Rez-de-Jardin 15545) | 196.9 | 196.9 | 111 | 111 | 1900 | 3000 | 3000 | 21900 | 330000 | Blanc | Blanc | 327022 | 327022 | 14.9652 | 111 | 2946.14 | 21852.2 | 21852.2 | ...de matériaux et couleurs = Blanc; ...de matériaux et couleurs - 1 = Blanc; ...de matériaux et couleurs - 2 = Blanc; ...de stratigraphies = default | IFC_Pset_Géométrie - Rayon: 277.964 cm; Point arc: [1 393,9; -1 048,7] cm; Centre: [1 575,4; -848,1] cm; Angle de la Tangente: 16.0006 deg
Enveloppe courbe 90232 | Rez-de-Jardin | Enveloppe courbe | 90232 | 367 | 9001 | 1977773087 | 1977773087 | 1 | 0 | 03 | 02 | Rez-de-Jardin | no | trapèze | 94.4715 | 170.4 | 0 | 65.3884 | 199.095 | 245.388 | HAUT Rez-de-Jardin (Rez-de-chaussée 1047) | 0 | <aucun> | Rez-de-Jardin (Rez-de-Jardin 15545) | 94.5 | 98.8 | 199.1 | 170.4 | 900 | 1400 | 1500 | 16700 | 250000 | Ivoire clair | Ivoire clair | 248888 | 248888 | 14.8676 | 177.199 | 1404.57 | 16740.3 | 16740.3 | ...de stratigraphies = default; ...de matériaux et couleurs = Ivoire clair; ...de matériaux et couleurs - 1 = Ivoire clair; ...de matériaux et couleurs - 2 = Ivoire clair | IFC_Pset_Géométrie - Rayon: 82.7795 cm; Point arc: [-1 136,6; -9,8] cm; Centre: [-1 084,0; -63,7] cm; Angle de la Tangente: 28.4051 deg
Enveloppe courbe 79037 | Rez-de-Jardin | Enveloppe courbe | 79037 | 367 | 9001 | 1977773087 | 1977773087 | 0 | 0 | 02 | 02 | Rez-de-Jardin | no | trapèze | 77.3435 | 187.698 | 0 | 23.1478 | 231.903 | 203.148 | HAUT Rez-de-Jardin (Rez-de-chaussée 1047) | 0 | <aucun> | Rez-de-Jardin (Rez-de-Jardin 15545) | 77.3 | 89.1 | 231.9 | 187.7 | 700 | 1200 | 1300 | 16200 | 240000 | Ivoire clair | Ivoire clair | 242679 | 242679 | 14.9555 | 209.8 | 1156.71 | 16226.7 | 16226.7 | ...de stratigraphies = default; ...de matériaux et couleurs = Ivoire clair; ...de matériaux et couleurs - 1 = Ivoire clair; ...de matériaux et couleurs - 2 = Ivoire clair | IFC_Pset_Géométrie - Rayon: 191.441 cm; Point arc: [-1 080,0; -132,0] cm; Centre: [-1 081,1; 51,9] cm; Angle de la Tangente: 7.28476 deg
Enveloppe courbe 78962 | Rez-de-Jardin | Enveloppe courbe | 78962 | 367 | 9001 | 1977773087 | 1977773087 | 1 | 0 | 01 | 02 | Rez-de-Jardin | no | trapèze | 111.09 | 187.698 | 0 | 82.186 | 170.4 | 262.186 | HAUT Rez-de-Jardin (Rez-de-chaussée 1047) | 0 | <aucun> | Rez-de-Jardin (Rez-de-Jardin 15545) | 111 | 112.4 | 187.7 | 170.4 | 1100 | 1600 | 1700 | 19700 | 300000 | Ivoire clair | Ivoire clair | 292025 | 292025 | 14.8408 | 177.127 | 1648.67 | 19677.1 | 19677.1 | ...de stratigraphies = default; ...de matériaux et couleurs = Ivoire clair; ...de matériaux et couleurs - 1 = Ivoire clair; ...de matériaux et couleurs - 2 = Ivoire clair | IFC_Pset_Géométrie - Rayon: 77.4461 cm; Point arc: [-1 152,9; -95,1] cm; Centre: [-1 089,8; -64,9] cm; Angle de la Tangente: 36.8039 deg
Enveloppe 374302 | Rez-de-chaussée | Enveloppe | 374302 | 366 | 9000 | 1977773087 | 1977773087 | 0 | 1 | 0640 | 03 | Rez-de-chaussée | no | rectangle | 193.658 | 182.783 | 0.0128504 | 89.656 | 182.783 | 269.656 | HAUT Rez-de-chaussée (Niveau 1 2343) | -295 | <aucun> | Rez-de-chaussée (Rez-de-chaussée 1047) | 193.7 | 193.7 | 182.8 | 182.8 | 2900 | 2900 | 2900 | 35400 | 530000 | Ivoire clair | Ivoire clair | 530960 | 113215 | 15 | 182.783 | 2904.87 | 35397.3 | 7547.66 | ...de stratigraphies = default; ...de matériaux et couleurs = Ivoire clair; ...de matériaux et couleurs - 1 = Ivoire clair; ...de matériaux et couleurs - 2 = Ivoire clair
Enveloppe 375014 | Rez-de-chaussée | Enveloppe | 375014 | 366 | 9000 | 1977773087 | 1977773087 | 0 | 1 | 0643 | 03 | Rez-de-chaussée | no | trapèze | 51.5757 | 1101.22 | 0.0128504 | 179.145 | 1102.1 | 359.145 | Couverture (Couverture 2134) | 0 | Toit795367 | Rez-de-chaussée (Rez-de-chaussée 1047) | 51.6 | 51.6 | 1102.1 | 1101.2 | 800 | 800 | 800 | 56800 | 850000 | Ivoire clair | Ivoire clair | 852284 | 852284 | 15 | 1101.66 | 773.636 | 56819 | 56819 | ...de stratigraphies = default; ...de matériaux et couleurs = Ivoire clair; ...de matériaux et couleurs - 1 = Ivoire clair; ...de matériaux et couleurs - 2 = Ivoire clair
Enveloppe 375184 | Rez-de-chaussée | Enveloppe | 375184 | 366 | 9000 | 1977773087 | 1977773087 | 0 | 1 | 0646 | 03 | Rez-de-chaussée | no | trapèze | 30.5546 | 1114.22 | 0.0128504 | 90.0752 | 1110.16 | 270.075 | Couverture (Couverture 2134) | 0 | Toit782750 | Rez-de-chaussée (Rez-de-chaussée 1047) | 30.6 | 30.9 | 1114.2 | 1110.2 | 500 | 500 | 500 | 34000 | 510000 | Ivoire clair | Ivoire clair | 509735 | 509735 | 15 | 1112.19 | 458.319 | 33982.3 | 33982.3 | ...de stratigraphies = default; ...de matériaux et couleurs = Ivoire clair; ...de matériaux et couleurs - 1 = Ivoire clair; ...de matériaux et couleurs - 2 = Ivoire clair
Enveloppe 375015 | Rez-de-chaussée | Enveloppe | 375015 | 366 | 9000 | 1977773087 | 1977773087 | 0 | 1 | 0644 | 03 | Rez-de-chaussée | no | rectangle | 134.241 | 477.795 | 0.0128504 | 89.2659 | 477.795 | 269.266 | HAUT Rez-de-chaussée (Niveau 1 2343) | 0.0128504 | <aucun> | Rez-de-chaussée (Rez-de-chaussée 1047) | 134.2 | 134.2 | 477.8 | 477.8 | 2000 | 2000 | 2000 | 64100 | 960000 | Ivoire clair | Ivoire clair | 962096 | 689455 | 15 | 477.795 | 2013.62 | 64139.7 | 45963.7 | ...de stratigraphies = default; ...de matériaux et couleurs = Ivoire clair; ...de matériaux et couleurs - 1 = Ivoire clair; ...de matériaux et couleurs - 2 = Ivoire clair
Enveloppe 375018 | Rez-de-chaussée | Enveloppe | 375018 | 366 | 9000 | 1977773087 | 1977773087 | 0 | 1 | 0645 | 03 | Rez-de-chaussée | no | trapèze | 30.1322 | 1109.96 | 0.0128504 | 44.7752 | 1114.05 | 224.775 | Couverture (Couverture 2134) | 0 | Toit782750 | Rez-de-chaussée (Rez-de-chaussée 1047) | 30.1 | 30.4 | 1114.1 | 1110 | 500 | 500 | 500 | 33500 | 500000 | Ivoire clair | Ivoire clair | 502608 | 502608 | 15 | 1112.01 | 451.982 | 33507.2 | 33507.2 | ...de stratigraphies = default; ...de matériaux et couleurs = Ivoire clair; ...de matériaux et couleurs - 1 = Ivoire clair; ...de matériaux et couleurs - 2 = Ivoire clair
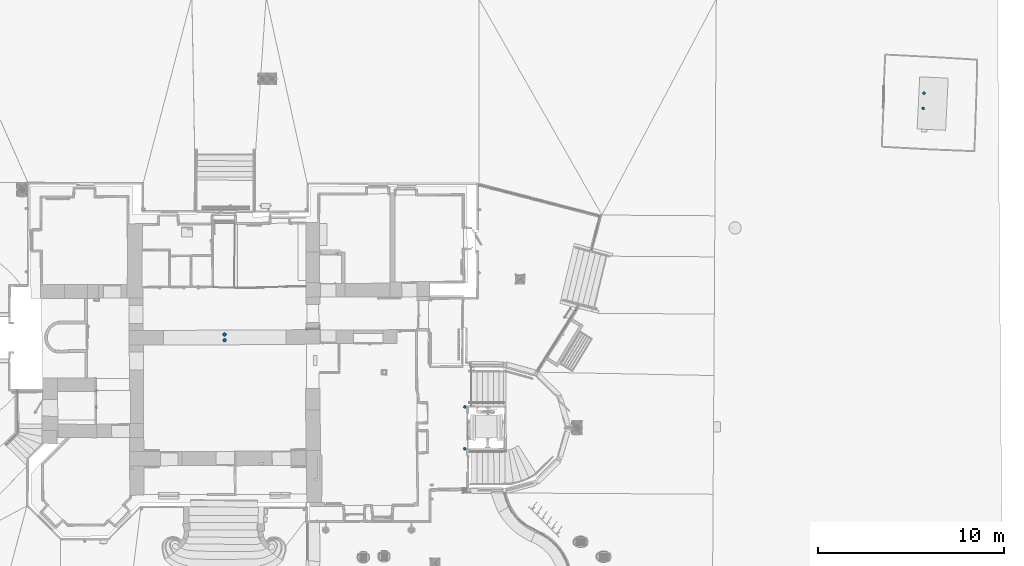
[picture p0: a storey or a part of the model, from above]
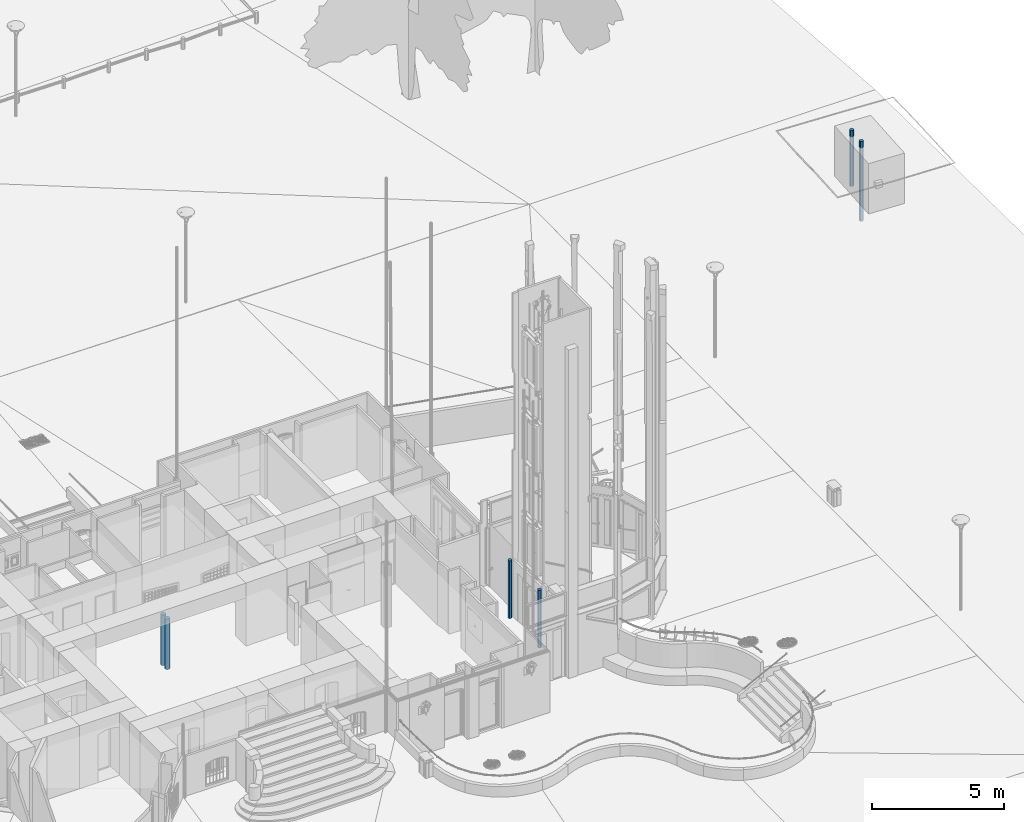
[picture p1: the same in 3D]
Properties of the parts of a building model (IFC2X3), part 21 of 37

# IfcWallStandardCase: default 150 (112)
Name | In | Description | __RECOGNIZE__, ID = IFC_Pset_Caractéristiques, ID | TPLG | TPLG_OD | 0, Crc | 1, Crc = 2, Crc | Alignment | ExternalFace | Numérotation | Numéro niveau | Titre niveau | Épaisseur VARIABLE | Forme en Élévation | Longueur (cm) = NominalLength (cm) | IFC_Pset_Géométrie, Hauteur (cm) = IFC_Pset_Géométrie_P1 (POINT initial), Hauteur (cm) | IFC_Pset_Géométrie, Cote (cm) = IFC_Pset_Géométrie_P1 (POINT initial), Cote (cm) = IFC_Pset_Géométrie_P2 (POINT final), Cote (cm) = IFC_Pset_Système de Référence Altimétrique_INFÉRIEUR, delta (cm) = IFC_Pset_Système de Référence Altimétrique_INFÉRIEUR, delta (P1) (cm) = IFC_Pset_Système de Référence Altimétrique_INFÉRIEUR, delta (P2) (cm) | IFC_Pset_Géométrie_P1 (POINT initial), Angle XY (deg) | IFC_Pset_Géométrie_P2 (POINT final), Hauteur (cm) | IFC_Pset_Géométrie_P2 (POINT final), Angle XY (deg) | IFC_Pset_Système de Référence Altimétrique_SUPÉRIEUR, NIVEAU | IFC_Pset_Système de Référence Altimétrique_SUPÉRIEUR, delta (cm) = IFC_Pset_Système de Référence Altimétrique_SUPÉRIEUR, delta (P1) (cm) = IFC_Pset_Système de Référence Altimétrique_SUPÉRIEUR, delta (P2) (cm) | sous Niveau | IFC_Pset_Système de Référence Altimétrique_INFÉRIEUR, NIVEAU | Longueur Pied (cm) | Longueur Tête (cm) | Hauteur Maximale (cm) | Hauteur Minimale (cm) | Surface en Plan (cm2) | Surface Pied (cm2) | Surface Tête (cm2) | Surface de la Paroi (cm2) | Volume (cm3) | Face gauche | Face droite = Face latérale | GrossVolume (cm3) | NetVolume (cm3) | NominalWidth (cm) | NominalHeight (cm) | GrossFootprintArea (cm2) = NetFootprintArea (cm2) | GrossSideArea (cm2) | NetSideArea (cm2) | Group
Enveloppe 373947 | Rez-de-chaussée | Enveloppe | 373947 | 366 | 9000 | 1977773087 | 1977773087 | 1 | 1 | 0632 | 03 | Rez-de-chaussée | no | trapèze | 53.4467 | 1110.76 | 0.0128504 | 89.6748 | 1093.25 | 269.675 | Couverture (Couverture 2134) | 0 | Toit783918 | Rez-de-chaussée (Rez-de-chaussée 1047) | 53.4 | 56.2 | 1110.8 | 1093.3 | 800 | 800 | 900 | 59200 | 890000 | Ivoire clair | Ivoire clair | 889113 | 889113 | 15 | 1109.03 | 801.7 | 59274.2 | 59274.2 | ...de stratigraphies = default; ...de matériaux et couleurs = Ivoire clair; ...de matériaux et couleurs - 1 = Ivoire clair; ...de matériaux et couleurs - 2 = Ivoire clair
Enveloppe 373412 | Rez-de-chaussée | Enveloppe | 373412 | 366 | 9000 | 1977773087 | 1977773087 | 1 | 1 | 0630 | 03 | Rez-de-chaussée | no | rectangle | 243.758 | 477.795 | 0.0128504 | 179.869 | 477.795 | 359.869 | HAUT Rez-de-chaussée (Niveau 1 2343) | 0.0128504 | <aucun> | Rez-de-chaussée (Rez-de-chaussée 1047) | 243.8 | 243.8 | 477.8 | 477.8 | 3700 | 3700 | 3700 | 116500 | 1750000 | Ivoire clair | Ivoire clair | 1746999 | 733932 | 15 | 477.795 | 3656.37 | 116467 | 48928.8 | ...de stratigraphies = default; ...de matériaux et couleurs = Ivoire clair; ...de matériaux et couleurs - 1 = Ivoire clair; ...de matériaux et couleurs - 2 = Ivoire clair
Enveloppe 373583 | Rez-de-chaussée | Enveloppe | 373583 | 366 | 9000 | 1977773087 | 1977773087 | 1 | 1 | 0631 | 03 | Rez-de-chaussée | no | rectangle | 173.831 | 477.795 | 0.0128504 | 179.842 | 477.795 | 359.842 | HAUT Rez-de-chaussée (Niveau 1 2343) | 0.0128504 | <aucun> | Rez-de-chaussée (Rez-de-chaussée 1047) | 173.8 | 173.8 | 477.8 | 477.8 | 2600 | 2600 | 2600 | 83000 | 1250000 | Ivoire clair | Ivoire clair | 1245832 | 539831 | 15 | 477.795 | 2607.46 | 83055.5 | 35988.7 | ...de stratigraphies = default; ...de matériaux et couleurs = Ivoire clair; ...de matériaux et couleurs - 1 = Ivoire clair; ...de matériaux et couleurs - 2 = Ivoire clair
Enveloppe 374089 | Rez-de-chaussée | Enveloppe | 374089 | 366 | 9000 | 1977773087 | 1977773087 | 1 | 1 | 0634 | 03 | Rez-de-chaussée | no | rectangle | 173.553 | 477.795 | 0.0128504 | 179.953 | 477.795 | 359.953 | HAUT Rez-de-chaussée (Niveau 1 2343) | 0.0128504 | <aucun> | Rez-de-chaussée (Rez-de-chaussée 1047) | 173.6 | 173.6 | 477.8 | 477.8 | 2600 | 2600 | 2600 | 82900 | 1240000 | Ivoire clair | Ivoire clair | 1243839 | 543592 | 15 | 477.795 | 2603.29 | 82922.6 | 36239.4 | ...de stratigraphies = default; ...de matériaux et couleurs = Ivoire clair; ...de matériaux et couleurs - 1 = Ivoire clair; ...de matériaux et couleurs - 2 = Ivoire clair
Enveloppe 374253 | Rez-de-chaussée | Enveloppe | 374253 | 366 | 9000 | 1977773087 | 1977773087 | 0 | 1 | 0637 | 03 | Rez-de-chaussée | no | rectangle | 174.962 | 465.783 | 0.0128504 | 89.6897 | 465.783 | 269.69 | HAUT Rez-de-chaussée (Niveau 1 2343) | -12 | <aucun> | Rez-de-chaussée (Rez-de-chaussée 1047) | 175 | 175 | 465.8 | 465.8 | 2600 | 2600 | 2600 | 81500 | 1220000 | Ivoire clair | Ivoire clair | 1222410 | 514442 | 15 | 465.783 | 2624.42 | 81494 | 34296.1 | ...de stratigraphies = default; ...de matériaux et couleurs = Ivoire clair; ...de matériaux et couleurs - 1 = Ivoire clair; ...de matériaux et couleurs - 2 = Ivoire clair
Enveloppe 374257 | Rez-de-chaussée | Enveloppe | 374257 | 366 | 9000 | 1977773087 | 1977773087 | 1 | 1 | 0638 | 03 | Rez-de-chaussée | no | rectangle | 51.9621 | 1088.9 | 0.0128504 | 179.547 | 1088.9 | 359.547 | HAUT Niveau 2 (Mezzanine 49003) | 1.5099e-11 | <aucun> | Rez-de-chaussée (Rez-de-chaussée 1047) | 52 | 52 | 1088.9 | 1088.9 | 800 | 800 | 800 | 56600 | 850000 | Ivoire clair | Ivoire clair | 848721 | 848721 | 15 | 1088.9 | 779.431 | 56581.4 | 56581.4 | ...de stratigraphies = default; ...de matériaux et couleurs = Ivoire clair; ...de matériaux et couleurs - 1 = Ivoire clair; ...de matériaux et couleurs - 2 = Ivoire clair
Enveloppe 374149 | Rez-de-chaussée | Enveloppe | 374149 | 366 | 9000 | 1977773087 | 1977773087 | 1 | 1 | 0635 | 03 | Rez-de-chaussée | no | trapèze | 51.2328 | 1106.76 | 0.0128504 | 179.562 | 1094.55 | 359.562 | Couverture (Couverture 2134) | 0 | Toit783918 | Rez-de-chaussée (Rez-de-chaussée 1047) | 51.2 | 52.6 | 1106.8 | 1094.6 | 800 | 800 | 900 | 56600 | 850000 | Ivoire clair | Ivoire clair | 849801 | 849801 | 15 | 1105.8 | 768.492 | 56653.4 | 56653.4 | ...de stratigraphies = default; ...de matériaux et couleurs = Ivoire clair; ...de matériaux et couleurs - 1 = Ivoire clair; ...de matériaux et couleurs - 2 = Ivoire clair
Enveloppe 374192 | Rez-de-chaussée | Enveloppe | 374192 | 366 | 9000 | 1977773087 | 1977773087 | 0 | 1 | 0636 | 03 | Rez-de-chaussée | no | trapèze | 52.1498 | 1107.06 | 0.0128504 | 89.5925 | 1094.43 | 269.592 | Couverture (Couverture 2134) | 0 | Toit783918 | Rez-de-chaussée (Rez-de-chaussée 1047) | 52.1 | 53.6 | 1107.1 | 1094.4 | 800 | 800 | 900 | 57600 | 860000 | Ivoire clair | Ivoire clair | 865364 | 865364 | 15 | 1106.25 | 782.247 | 57690.9 | 57690.9 | ...de stratigraphies = default; ...de matériaux et couleurs = Ivoire clair; ...de matériaux et couleurs - 1 = Ivoire clair; ...de matériaux et couleurs - 2 = Ivoire clair
Enveloppe 376261 | Rez-de-chaussée | Enveloppe | 376261 | 366 | 9000 | 1977773087 | 1977773087 | 1 | 1 | 0657 | 03 | Rez-de-chaussée | no | rectangle | 173.791 | 477.795 | 0.0128504 | 0.0273445 | 477.795 | 180.027 | HAUT Rez-de-chaussée (Niveau 1 2343) | 0.0128504 | <aucun> | Rez-de-chaussée (Rez-de-chaussée 1047) | 173.8 | 173.8 | 477.8 | 477.8 | 2600 | 2600 | 2600 | 83000 | 1250000 | Ivoire clair | Ivoire clair | 1245548 | 617355 | 15 | 477.795 | 2606.87 | 83036.6 | 41157 | ...de stratigraphies = default; ...de matériaux et couleurs = Ivoire clair; ...de matériaux et couleurs - 1 = Ivoire clair; ...de matériaux et couleurs - 2 = Ivoire clair
Enveloppe 376323 | Rez-de-chaussée | Enveloppe | 376323 | 366 | 9000 | 1977773087 | 1977773087 | 0 | 1 | 0658 | 03 | Rez-de-chaussée | no | rectangle | 373.508 | 477.795 | 0.0128504 | 179.781 | 477.795 | 359.781 | HAUT Rez-de-chaussée (Niveau 1 2343) | 0.0128504 | <aucun> | Rez-de-chaussée (Rez-de-chaussée 1047) | 373.5 | 373.5 | 477.8 | 477.8 | 5600 | 5600 | 5600 | 178500 | 2680000 | Ivoire clair | Ivoire clair | 2676905 | 900400 | 15 | 477.795 | 5602.62 | 178460 | 60026.7 | ...de stratigraphies = default; ...de matériaux et couleurs = Ivoire clair; ...de matériaux et couleurs - 1 = Ivoire clair; ...de matériaux et couleurs - 2 = Ivoire clair
Enveloppe 378802 | Rez-de-chaussée | Enveloppe | 378802 | 366 | 9000 | 1977773087 | 1977773087 | 0 | 0 | 0665 | 03 | Rez-de-chaussée | no | rectangle | 172.466 | 477.795 | 0.0128504 | 179.754 | 477.795 | 359.754 | HAUT Rez-de-chaussée (Niveau 1 2343) | 0.0128504 | <aucun> | Rez-de-chaussée (Rez-de-chaussée 1047) | 172.5 | 172.5 | 477.8 | 477.8 | 2600 | 2600 | 2600 | 82400 | 1240000 | Ivoire clair | Ivoire clair | 1236052 | 601392 | 15 | 477.795 | 2586.99 | 82403.5 | 40092.8 | ...de stratigraphies = default; ...de matériaux et couleurs = Ivoire clair; ...de matériaux et couleurs - 1 = Ivoire clair; ...de matériaux et couleurs - 2 = Ivoire clair
Enveloppe 375675 | Rez-de-chaussée | Enveloppe | 375675 | 366 | 9000 | 1977773087 | 1977773087 | 1 | 1 | 0650 | 03 | Rez-de-chaussée | no | trapèze | 30.3956 | 1113.22 | 0.0128504 | 0.0915388 | 1109.45 | 180.092 | Couverture (Couverture 2134) | 0 | Toit782750 | Rez-de-chaussée (Rez-de-chaussée 1047) | 30.4 | 30.6 | 1113.2 | 1109.4 | 500 | 500 | 500 | 33800 | 510000 | Ivoire clair | Ivoire clair | 506695 | 506695 | 15 | 1111.33 | 455.934 | 33779.7 | 33779.7 | ...de stratigraphies = default; ...de matériaux et couleurs = Ivoire clair; ...de matériaux et couleurs - 1 = Ivoire clair; ...de matériaux et couleurs - 2 = Ivoire clair
Enveloppe 375798 | Rez-de-chaussée | Enveloppe | 375798 | 366 | 9000 | 1977773087 | 1977773087 | 1 | 1 | 0651 | 03 | Rez-de-chaussée | no | rectangle | 246.965 | 477.795 | 0.0128504 | 44.8748 | 477.795 | 224.875 | HAUT Rez-de-chaussée (Niveau 1 2343) | 0.0128504 | <aucun> | Rez-de-chaussée (Rez-de-chaussée 1047) | 247 | 247 | 477.8 | 477.8 | 3700 | 3700 | 3700 | 118000 | 1770000 | Ivoire clair | Ivoire clair | 1769979 | 1063018 | 15 | 477.795 | 3704.47 | 117999 | 70867.9 | ...de stratigraphies = default; ...de matériaux et couleurs = Ivoire clair; ...de matériaux et couleurs - 1 = Ivoire clair; ...de matériaux et couleurs - 2 = Ivoire clair
Enveloppe 375460 | Rez-de-chaussée | Enveloppe | 375460 | 366 | 9000 | 1977773087 | 1977773087 | 0 | 1 | 0648 | 03 | Rez-de-chaussée | no | rectangle | 252.383 | 477.795 | 0.0128504 | 135.126 | 477.795 | 315.126 | HAUT Rez-de-chaussée (Niveau 1 2343) | 0.0128504 | <aucun> | Rez-de-chaussée (Rez-de-chaussée 1047) | 252.4 | 252.4 | 477.8 | 477.8 | 3800 | 3800 | 3800 | 120600 | 1810000 | Ivoire clair | Ivoire clair | 1808810 | 1101222 | 15 | 477.795 | 3785.74 | 120587 | 73414.8 | ...de stratigraphies = default; ...de matériaux et couleurs = Ivoire clair; ...de matériaux et couleurs - 1 = Ivoire clair; ...de matériaux et couleurs - 2 = Ivoire clair
Enveloppe 375632 | Rez-de-chaussée | Enveloppe | 375632 | 366 | 9000 | 1977773087 | 1977773087 | 0 | 1 | 0649 | 03 | Rez-de-chaussée | no | trapèze | 30.3977 | 1113.15 | 0.0128504 | 179.361 | 1109.97 | 359.361 | Couverture (Couverture 2134) | 0 | Toit782750 | Rez-de-chaussée (Rez-de-chaussée 1047) | 30.4 | 30.6 | 1113.2 | 1110 | 500 | 500 | 500 | 33800 | 510000 | Ivoire clair | Ivoire clair | 506834 | 506834 | 15 | 1111.56 | 455.965 | 33788.9 | 33788.9 | ...de stratigraphies = default; ...de matériaux et couleurs = Ivoire clair; ...de matériaux et couleurs - 1 = Ivoire clair; ...de matériaux et couleurs - 2 = Ivoire clair
Enveloppe 373229 | Rez-de-chaussée | Enveloppe | 373229 | 366 | 9000 | 1977773087 | 1977773087 | 1 | 1 | 0629 | 03 | Rez-de-chaussée | no | rectangle | 175.2 | 477.795 | 0.0128504 | 179.869 | 477.795 | 359.869 | HAUT Rez-de-chaussée (Niveau 1 2343) | 0.0128504 | <aucun> | Rez-de-chaussée (Rez-de-chaussée 1047) | 175.2 | 175.2 | 477.8 | 477.8 | 2600 | 2600 | 2600 | 83700 | 1260000 | Ivoire clair | Ivoire clair | 1255645 | 553150 | 15 | 477.795 | 2628 | 83709.6 | 36876.6 | ...de stratigraphies = default; ...de matériaux et couleurs = Ivoire clair; ...de matériaux et couleurs - 1 = Ivoire clair; ...de matériaux et couleurs - 2 = Ivoire clair
Enveloppe 369434 | Rez-de-chaussée | Enveloppe | 369434 | 366 | 9000 | 1977773087 | 1977773087 | 1 | 1 | 0604 | 03 | Rez-de-chaussée | no | trapèze | 34.5102 | 1116.63 | 0.0128504 | 179.369 | 1115.74 | 359.369 | Couverture (Couverture 2134) | 0 | Toit793924 | Rez-de-chaussée (Rez-de-chaussée 1047) | 34.5 | 34.5 | 1116.6 | 1115.7 | 500 | 500 | 500 | 38500 | 580000 | Ivoire clair | Ivoire clair | 577798 | 577798 | 15 | 1116.19 | 517.654 | 38519.8 | 38519.8 | ...de stratigraphies = default; ...de matériaux et couleurs = Ivoire clair; ...de matériaux et couleurs - 1 = Ivoire clair; ...de matériaux et couleurs - 2 = Ivoire clair
Enveloppe 369477 | Rez-de-chaussée | Enveloppe | 369477 | 366 | 9000 | 1977773087 | 1977773087 | 1 | 1 | 0605 | 03 | Rez-de-chaussée | no | rectangle | 342.96 | 477.795 | 0.0128504 | 179.855 | 477.795 | 359.855 | HAUT Rez-de-chaussée (Niveau 1 2343) | 0.0128504 | <aucun> | Rez-de-chaussée (Rez-de-chaussée 1047) | 343 | 343 | 477.8 | 477.8 | 5100 | 5100 | 5100 | 163900 | 2460000 | Ivoire clair | Ivoire clair | 2457972 | 1049808 | 15 | 477.795 | 5144.4 | 163865 | 69987.2 | ...de stratigraphies = default; ...de matériaux et couleurs = Ivoire clair; ...de matériaux et couleurs - 1 = Ivoire clair; ...de matériaux et couleurs - 2 = Ivoire clair
Enveloppe 368683 | Rez-de-chaussée | Enveloppe | 368683 | 366 | 9000 | 1977773087 | 1977773087 | 1 | 1 | 0602 | 03 | Rez-de-chaussée | no | trapèze | 50.3825 | 1114.65 | 0.0128504 | 90.4865 | 1104.69 | 270.486 | Couverture (Couverture 2134) | 0 | Toit793924 | Rez-de-chaussée (Rez-de-chaussée 1047) | 50.4 | 51.4 | 1114.6 | 1104.7 | 800 | 800 | 800 | 56200 | 840000 | Ivoire clair | Ivoire clair | 842186 | 842186 | 15 | 1114.39 | 755.738 | 56145.7 | 56145.7 | ...de stratigraphies = default; ...de matériaux et couleurs = Ivoire clair; ...de matériaux et couleurs - 1 = Ivoire clair; ...de matériaux et couleurs - 2 = Ivoire clair
Enveloppe 367898 | Rez-de-chaussée | Enveloppe | 367898 | 366 | 9000 | 1977773087 | 1977773087 | 1 | 1 | 0596 | 03 | Rez-de-chaussée | no | trapèze | 49.7155 | 1111.26 | 0.0128504 | 89.8082 | 1115.3 | 269.808 | Couverture (Couverture 2134) | 0 | Toit793924 | Rez-de-chaussée (Rez-de-chaussée 1047) | 49.7 | 49.9 | 1115.3 | 1111.3 | 700 | 700 | 700 | 55300 | 830000 | Ivoire clair | Ivoire clair | 830208 | 830208 | 15 | 1113.28 | 745.732 | 55347.2 | 55347.2 | ...de stratigraphies = default; ...de matériaux et couleurs = Ivoire clair; ...de matériaux et couleurs - 1 = Ivoire clair; ...de matériaux et couleurs - 2 = Ivoire clair
Enveloppe 368252 | Rez-de-chaussée | Enveloppe | 368252 | 366 | 9000 | 1977773087 | 1977773087 | 1 | 1 | 0599 | 03 | Rez-de-chaussée | no | rectangle | 173.995 | 477.795 | 0.0128504 | 89.8082 | 477.795 | 269.808 | HAUT Rez-de-chaussée (Niveau 1 2343) | 0.0128504 | <aucun> | Rez-de-chaussée (Rez-de-chaussée 1047) | 174 | 174 | 477.8 | 477.8 | 2600 | 2600 | 2600 | 83100 | 1250000 | Ivoire clair | Ivoire clair | 1247011 | 509621 | 15 | 477.795 | 2609.93 | 83134 | 33974.8 | ...de stratigraphies = default; ...de matériaux et couleurs = Ivoire clair; ...de matériaux et couleurs - 1 = Ivoire clair; ...de matériaux et couleurs - 2 = Ivoire clair
Enveloppe 401431 | Rez-de-chaussée | Enveloppe | 401431 | 366 | 9000 | 1977773087 | 1977773087 | 0 | 1 | 0669 | 03 | Rez-de-chaussée | no | rectangle | 284.057 | 657.91 | 184 | 89.656 | 657.91 | 269.656 | HAUT Niveau 1 (Niveau 2 13545) | -12 | <aucun> | Rez-de-chaussée (Rez-de-chaussée 1047) | 284.1 | 284.1 | 657.9 | 657.9 | 4300 | 4300 | 4300 | 186900 | 2800000 | Ivoire clair | Ivoire clair | 2803259 | 1381114 | 15 | 657.91 | 4260.85 | 186884 | 92074.3 | ...de stratigraphies = default; ...de matériaux et couleurs = Ivoire clair; ...de matériaux et couleurs - 1 = Ivoire clair; ...de matériaux et couleurs - 2 = Ivoire clair
Enveloppe 680482 | Rez-de-chaussée | Enveloppe | 680482 | 366 | 9000 | 1977773087 | 1977773087 | 1 | 1 | 1040 | 03 | Rez-de-chaussée | no | rectangle | 305.568 | 33.7954 | 180 | 29.28 | 33.7954 | 209.28 | HAUT Rez-de-chaussée (Niveau 1 2343) | -264 | <aucun> | Rez-de-chaussée (Rez-de-chaussée 1047) | 305.6 | 305.6 | 33.8 | 33.8 | 4600 | 4600 | 4600 | 10300 | 150000 | Ivoire clair | Ivoire clair | 154902 | 154902 | 15 | 33.7954 | 4583.52 | 10326.8 | 10326.8 | ...de stratigraphies = default; ...de matériaux et couleurs = Ivoire clair; ...de matériaux et couleurs - 1 = Ivoire clair; ...de matériaux et couleurs - 2 = Ivoire clair
Enveloppe 691032 | Rez-de-chaussée | Enveloppe | 691032 | 366 | 9000 | 1977773087 | 1977773087 | 0 | 1 | 1041 | 03 | Rez-de-chaussée | no | rectangle | 304.81 | 33.7954 | 180 | 150.569 | 33.7954 | 330.569 | HAUT Rez-de-chaussée (Niveau 1 2343) | -264 | <aucun> | Rez-de-chaussée (Rez-de-chaussée 1047) | 304.8 | 304.8 | 33.8 | 33.8 | 4600 | 4600 | 4600 | 10300 | 150000 | Ivoire clair | Ivoire clair | 154518 | 154518 | 15 | 33.7954 | 4572.16 | 10301.2 | 10301.2 | ...de stratigraphies = default; ...de matériaux et couleurs = Ivoire clair; ...de matériaux et couleurs - 1 = Ivoire clair; ...de matériaux et couleurs - 2 = Ivoire clair
Enveloppe 710091 | Rez-de-chaussée | Enveloppe | 710091 | 366 | 9000 | 1977773087 | 1977773087 | 1 | 1 | 1045 | 03 | Rez-de-chaussée | no | rectangle | 204.37 | 15.3982 | 62.3972 | 90.0947 | 15.3982 | 270.095 | HAUT Rez-de-chaussée (Niveau 1 2343) | -400 | <aucun> | Rez-de-chaussée (Rez-de-chaussée 1047) | 204.4 | 204.4 | 15.4 | 15.4 | 3100 | 3100 | 3100 | 3100 | 50000 | Ivoire clair | Ivoire clair | 47203.9 | 47203.9 | 15 | 15.3982 | 3065.55 | 3146.93 | 3146.93 | ...de stratigraphies = default; ...de matériaux et couleurs = Ivoire clair; ...de matériaux et couleurs - 1 = Ivoire clair; ...de matériaux et couleurs - 2 = Ivoire clair
Enveloppe 691254 | Rez-de-chaussée | Enveloppe | 691254 | 366 | 9000 | 1977773087 | 1977773087 | 1 | 1 | 1042 | 03 | Rez-de-chaussée | no | rectangle | 203.907 | 27.7954 | 310 | 89.6387 | 27.7954 | 269.639 | HAUT Rez-de-chaussée (Niveau 1 2343) | -140 | <aucun> | Rez-de-chaussée (Rez-de-chaussée 1047) | 203.9 | 203.9 | 27.8 | 27.8 | 3100 | 3100 | 3100 | 5700 | 90000 | Ivoire clair | Ivoire clair | 85015.2 | 85015.2 | 15 | 27.7954 | 3058.61 | 5667.68 | 5667.68 | ...de stratigraphies = default; ...de matériaux et couleurs = Ivoire clair; ...de matériaux et couleurs - 1 = Ivoire clair; ...de matériaux et couleurs - 2 = Ivoire clair
Enveloppe 366066 | Rez-de-chaussée | Enveloppe | 366066 | 366 | 9000 | 1977773087 | 1977773087 | 1 | 1 | 0586 | 03 | Rez-de-chaussée | no | trapèze | 49.6704 | 1114.35 | -2 | 0.106209 | 1103.41 | 180.106 | Couverture (Couverture 2134) | 0 | Toit793923 | Rez-de-chaussée (Rez-de-chaussée 1047) | 49.7 | 50.9 | 1114.3 | 1103.4 | 700 | 700 | 800 | 55400 | 830000 | Ivoire clair | Ivoire clair | 829793 | 829793 | 15 | 1113.73 | 745.056 | 55319.5 | 55319.5 | ...de stratigraphies = default; ...de matériaux et couleurs = Ivoire clair; ...de matériaux et couleurs - 1 = Ivoire clair; ...de matériaux et couleurs - 2 = Ivoire clair
Enveloppe 365506 | Rez-de-chaussée | Enveloppe | 365506 | 366 | 9000 | 1977773087 | 1977773087 | 1 | 1 | 0583 | 03 | Rez-de-chaussée | no | rectangle | 344.031 | 477.795 | 0.0128504 | 0.106209 | 477.795 | 180.106 | HAUT Rez-de-chaussée (Niveau 1 2343) | 0.0128504 | <aucun> | Rez-de-chaussée (Rez-de-chaussée 1047) | 344 | 344 | 477.8 | 477.8 | 5200 | 5200 | 5200 | 164400 | 2470000 | Ivoire clair | Ivoire clair | 2465645 | 1061835 | 15 | 477.795 | 5160.46 | 164376 | 70789 | ...de stratigraphies = default; ...de matériaux et couleurs = Ivoire clair; ...de matériaux et couleurs - 1 = Ivoire clair; ...de matériaux et couleurs - 2 = Ivoire clair
Enveloppe 366190 | Rez-de-chaussée | Enveloppe | 366190 | 366 | 9000 | 1977773087 | 1977773087 | 1 | 1 | 0587 | 03 | Rez-de-chaussée | no | trapèze | 49.2721 | 1102.43 | -2 | 89.9542 | 1115.35 | 269.954 | Couverture (Couverture 2134) | 0 | Toit793923 | Rez-de-chaussée (Rez-de-chaussée 1047) | 49.3 | 51 | 1115.3 | 1102.4 | 700 | 700 | 900 | 55000 | 820000 | Ivoire clair | Ivoire clair | 823817 | 823817 | 15 | 1114.65 | 739.081 | 54921.1 | 54921.1 | ...de stratigraphies = default; ...de matériaux et couleurs = Ivoire clair; ...de matériaux et couleurs - 1 = Ivoire clair; ...de matériaux et couleurs - 2 = Ivoire clair
Enveloppe 367336 | Rez-de-chaussée | Enveloppe | 367336 | 366 | 9000 | 1977773087 | 1977773087 | 1 | 1 | 0591 | 03 | Rez-de-chaussée | no | rectangle | 49.9959 | 477.795 | 0.0128504 | 90.3425 | 477.795 | 270.343 | HAUT Rez-de-chaussée (Niveau 1 2343) | 0.0128504 | <aucun> | Rez-de-chaussée (Rez-de-chaussée 1047) | 50 | 50 | 477.8 | 477.8 | 800 | 800 | 800 | 23900 | 360000 | Ivoire clair | Ivoire clair | 358317 | 358317 | 15 | 477.795 | 749.939 | 23887.8 | 23887.8 | ...de stratigraphies = default; ...de matériaux et couleurs = Ivoire clair; ...de matériaux et couleurs - 1 = Ivoire clair; ...de matériaux et couleurs - 2 = Ivoire clair
Enveloppe 366460 | Rez-de-chaussée | Enveloppe | 366460 | 366 | 9000 | 1977773087 | 1977773087 | 1 | 1 | 0588 | 03 | Rez-de-chaussée | no | rectangle | 19.9985 | 447.783 | 0.0128504 | 89.994 | 447.783 | 269.994 | HAUT Rez-de-chaussée (Niveau 1 2343) | -30 | <aucun> | Rez-de-chaussée (Rez-de-chaussée 1047) | 20 | 20 | 447.8 | 447.8 | 300 | 300 | 300 | 9000 | 140000 | Ivoire clair | Ivoire clair | 134325 | 134325 | 15 | 447.783 | 299.978 | 8954.99 | 8954.99 | ...de stratigraphies = default; ...de matériaux et couleurs = Ivoire clair; ...de matériaux et couleurs - 1 = Ivoire clair; ...de matériaux et couleurs - 2 = Ivoire clair
Enveloppe 364581 | Rez-de-chaussée | Enveloppe | 364581 | 366 | 9000 | 1977773087 | 1977773087 | 1 | 1 | 0581 | 03 | Rez-de-chaussée | no | rectangle | 50.6488 | 1100.91 | -2 | 0.106209 | 1100.91 | 180.106 | HAUT Niveau 2 (Mezzanine 49003) | 10 | <aucun> | Rez-de-chaussée (Rez-de-chaussée 1047) | 50.6 | 50.6 | 1100.9 | 1100.9 | 800 | 800 | 800 | 55700 | 840000 | Ivoire clair | Ivoire clair | 836396 | 836396 | 15 | 1100.91 | 759.731 | 55759.7 | 55759.7 | ...de stratigraphies = default; ...de matériaux et couleurs = Ivoire clair; ...de matériaux et couleurs - 1 = Ivoire clair; ...de matériaux et couleurs - 2 = Ivoire clair
Enveloppe 364866 | Rez-de-chaussée | Enveloppe | 364866 | 366 | 9000 | 1977773087 | 1977773087 | 0 | 1 | 0582 | 03 | Rez-de-chaussée | no | rectangle | 35.8028 | 1100.91 | -2 | 90.1681 | 1100.91 | 270.168 | HAUT Niveau 2 (Mezzanine 49003) | 10 | <aucun> | Rez-de-chaussée (Rez-de-chaussée 1047) | 35.8 | 35.8 | 1100.9 | 1100.9 | 500 | 500 | 500 | 39400 | 590000 | Ivoire clair | Ivoire clair | 591235 | 591235 | 15 | 1100.91 | 537.042 | 39415.7 | 39415.7 | ...de stratigraphies = default; ...de matériaux et couleurs = Ivoire clair; ...de matériaux et couleurs - 1 = Ivoire clair; ...de matériaux et couleurs - 2 = Ivoire clair
Enveloppe 366762 | Rez-de-chaussée | Enveloppe | 366762 | 366 | 9000 | 1977773087 | 1977773087 | 1 | 1 | 0589 | 03 | Rez-de-chaussée | no | rectangle | 323.792 | 447.783 | 0.0128504 | 89.6761 | 447.783 | 269.676 | HAUT Rez-de-chaussée (Niveau 1 2343) | -30 | <aucun> | Rez-de-chaussée (Rez-de-chaussée 1047) | 323.8 | 323.8 | 447.8 | 447.8 | 4900 | 4900 | 4900 | 145000 | 2180000 | Ivoire clair | Ivoire clair | 2174824 | 1380985 | 15 | 447.783 | 4856.88 | 144988 | 92065.7 | ...de stratigraphies = default; ...de matériaux et couleurs = Ivoire clair; ...de matériaux et couleurs - 1 = Ivoire clair; ...de matériaux et couleurs - 2 = Ivoire clair
Enveloppe 425741 | Niveau 1 | Enveloppe | 425741 | 366 | 9000 | 1908701706 | 1977773087 | 0 | 1 | 0715 | 04 | Niveau 1 | no | rectangle | 30.1234 | 376.102 | 0.0128504 | 135.126 | 376.102 | 315.126 | HAUT Niveau 1 (Niveau 2 13545) | 6.75016e-12 | <aucun> | Niveau 1 (Niveau 1 2343) | 30.1 | 30.1 | 376.1 | 376.1 | 500 | 500 | 500 | 11300 | 170000 | Gris lumière | Ivoire clair | 169942 | 169942 | 15 | 376.102 | 451.851 | 11329.5 | 11329.5 | ...de stratigraphies = default; ...de matériaux et couleurs - 1 = Ivoire clair; ...de matériaux et couleurs - 2 = Ivoire clair; ...de matériaux et couleurs = Gris lumière
Enveloppe 425744 | Niveau 1 | Enveloppe | 425744 | 366 | 9000 | 1908701706 | 1977773087 | 1 | 1 | 0716 | 04 | Niveau 1 | no | rectangle | 28.7622 | 376.102 | 0.0128504 | 44.8748 | 376.102 | 224.875 | HAUT Niveau 1 (Niveau 2 13545) | 6.75016e-12 | <aucun> | Niveau 1 (Niveau 1 2343) | 28.8 | 28.8 | 376.1 | 376.1 | 400 | 400 | 400 | 10800 | 160000 | Gris lumière | Ivoire clair | 162263 | 162263 | 15 | 376.102 | 431.433 | 10817.5 | 10817.5 | ...de stratigraphies = default; ...de matériaux et couleurs - 1 = Ivoire clair; ...de matériaux et couleurs - 2 = Ivoire clair; ...de matériaux et couleurs = Gris lumière
Enveloppe 425630 | Niveau 1 | Enveloppe | 425630 | 366 | 9000 | 1908701706 | 1977773087 | 0 | 1 | 0713 | 04 | Niveau 1 | no | rectangle | 24.7621 | 376.102 | 0.0128504 | 134.119 | 376.102 | 314.119 | HAUT Niveau 1 (Niveau 2 13545) | 6.75016e-12 | <aucun> | Niveau 1 (Niveau 1 2343) | 24.8 | 24.8 | 376.1 | 376.1 | 400 | 400 | 400 | 9300 | 140000 | Gris lumière | Ivoire clair | 139696 | 139696 | 15 | 376.102 | 371.432 | 9313.09 | 9313.09 | ...de stratigraphies = default; ...de matériaux et couleurs - 1 = Ivoire clair; ...de matériaux et couleurs - 2 = Ivoire clair; ...de matériaux et couleurs = Gris lumière
Enveloppe 425655 | Niveau 1 | Enveloppe | 425655 | 366 | 9000 | 1908701706 | 1977773087 | 0 | 1 | 0714 | 04 | Niveau 1 | no | rectangle | 152.554 | 376.102 | 0.0128504 | 135.126 | 376.102 | 315.126 | HAUT Niveau 1 (Niveau 2 13545) | 6.75016e-12 | <aucun> | Niveau 1 (Niveau 1 2343) | 152.6 | 152.6 | 376.1 | 376.1 | 2300 | 2300 | 2300 | 57400 | 860000 | Gris lumière | Ivoire clair | 860640 | 431377 | 15 | 376.102 | 2288.31 | 57376 | 28758.5 | ...de stratigraphies = default; ...de matériaux et couleurs - 1 = Ivoire clair; ...de matériaux et couleurs - 2 = Ivoire clair; ...de matériaux et couleurs = Gris lumière
Enveloppe 425790 | Niveau 1 | Enveloppe | 425790 | 366 | 9000 | 1908701706 | 1977773087 | 1 | 1 | 0717 | 04 | Niveau 1 | no | rectangle | 153.274 | 376.102 | 0.0128504 | 44.8748 | 376.102 | 224.875 | HAUT Niveau 1 (Niveau 2 13545) | 6.75016e-12 | <aucun> | Niveau 1 (Niveau 1 2343) | 153.3 | 153.3 | 376.1 | 376.1 | 2300 | 2300 | 2300 | 57700 | 870000 | Gris lumière | Ivoire clair | 864699 | 434693 | 15 | 376.102 | 2299.11 | 57646.6 | 28979.6 | ...de stratigraphies = default; ...de matériaux et couleurs - 1 = Ivoire clair; ...de matériaux et couleurs - 2 = Ivoire clair; ...de matériaux et couleurs = Gris lumière
Enveloppe 425975 | Niveau 1 | Enveloppe | 425975 | 366 | 9000 | 1908701706 | 1977773087 | 0 | 1 | 0720 | 04 | Niveau 1 | no | rectangle | 153.286 | 376.102 | 0.0128504 | 179.754 | 376.102 | 359.754 | HAUT Niveau 1 (Niveau 2 13545) | 6.75016e-12 | <aucun> | Niveau 1 (Niveau 1 2343) | 153.3 | 153.3 | 376.1 | 376.1 | 2300 | 2300 | 2300 | 57700 | 870000 | Gris lumière | Ivoire clair | 864769 | 380643 | 15 | 376.102 | 2299.29 | 57651.3 | 25376.2 | ...de stratigraphies = default; ...de matériaux et couleurs - 1 = Ivoire clair; ...de matériaux et couleurs - 2 = Ivoire clair; ...de matériaux et couleurs = Gris lumière
Enveloppe 426075 | Niveau 1 | Enveloppe | 426075 | 366 | 9000 | 1908701706 | 1977773087 | 0 | 1 | 0721 | 04 | Niveau 1 | no | rectangle | 153.663 | 376.102 | 0.0128504 | 179.781 | 376.102 | 359.781 | HAUT Niveau 1 (Niveau 2 13545) | 6.75016e-12 | <aucun> | Niveau 1 (Niveau 1 2343) | 153.7 | 153.7 | 376.1 | 376.1 | 2300 | 2300 | 2300 | 57800 | 870000 | Gris lumière | Ivoire clair | 866894 | 382768 | 15 | 376.102 | 2304.94 | 57793 | 25517.8 | ...de stratigraphies = default; ...de matériaux et couleurs - 1 = Ivoire clair; ...de matériaux et couleurs - 2 = Ivoire clair; ...de matériaux et couleurs = Gris lumière
Enveloppe 425890 | Niveau 1 | Enveloppe | 425890 | 366 | 9000 | 1908701706 | 1977773087 | 0 | 1 | 0719 | 04 | Niveau 1 | no | rectangle | 153.432 | 376.102 | 0.0128504 | 179.754 | 376.102 | 359.754 | HAUT Niveau 1 (Niveau 2 13545) | 6.75016e-12 | <aucun> | Niveau 1 (Niveau 1 2343) | 153.4 | 153.4 | 376.1 | 376.1 | 2300 | 2300 | 2300 | 57700 | 870000 | Gris lumière | Ivoire clair | 865591 | 383634 | 15 | 376.102 | 2301.48 | 57706.1 | 25575.6 | ...de stratigraphies = default; ...de matériaux et couleurs - 1 = Ivoire clair; ...de matériaux et couleurs - 2 = Ivoire clair; ...de matériaux et couleurs = Gris lumière
Enveloppe 425479 | Niveau 1 | Enveloppe | 425479 | 366 | 9000 | 1908701706 | 1977773087 | 0 | 1 | 0711 | 04 | Niveau 1 | no | rectangle | 164.149 | 376.102 | 0.0128504 | 89.6897 | 376.102 | 269.69 | HAUT Niveau 1 (Niveau 2 13545) | 6.75016e-12 | <aucun> | Niveau 1 (Niveau 1 2343) | 164.1 | 164.1 | 376.1 | 376.1 | 2500 | 2500 | 2500 | 61700 | 930000 | Gris lumière | Ivoire clair | 926054 | 495520 | 15 | 376.102 | 2462.24 | 61737 | 33034.7 | ...de stratigraphies = default; ...de matériaux et couleurs - 1 = Ivoire clair; ...de matériaux et couleurs - 2 = Ivoire clair; ...de matériaux et couleurs = Gris lumière
Enveloppe 425544 | Niveau 1 | Enveloppe | 425544 | 366 | 9000 | 1908701706 | 1977773087 | 0 | 1 | 0712 | 04 | Niveau 1 | no | rectangle | 135.225 | 374.102 | 0.0128504 | 89.2659 | 374.102 | 269.266 | HAUT Niveau 1 (Niveau 2 13545) | -2 | <aucun> | Niveau 1 (Niveau 1 2343) | 135.2 | 135.2 | 374.1 | 374.1 | 2000 | 2000 | 2000 | 50600 | 760000 | Gris lumière | Ivoire clair | 758818 | 587355 | 15 | 374.102 | 2028.37 | 50587.9 | 39157 | ...de stratigraphies = default; ...de matériaux et couleurs - 1 = Ivoire clair; ...de matériaux et couleurs - 2 = Ivoire clair; ...de matériaux et couleurs = Gris lumière
Enveloppe 426758 | Niveau 1 | Enveloppe | 426758 | 366 | 9000 | 1908701706 | 1977773087 | 1 | 1 | 0731 | 04 | Niveau 1 | no | rectangle | 159.645 | 376.102 | 0.0128504 | 179.869 | 376.102 | 359.869 | HAUT Niveau 1 (Niveau 2 13545) | 6.75016e-12 | <aucun> | Niveau 1 (Niveau 1 2343) | 159.6 | 159.6 | 376.1 | 376.1 | 2400 | 2400 | 2400 | 60000 | 900000 | Gris lumière | Ivoire clair | 900645 | 470628 | 15 | 376.102 | 2394.68 | 60043 | 31375.2 | ...de stratigraphies = default; ...de matériaux et couleurs - 1 = Ivoire clair; ...de matériaux et couleurs - 2 = Ivoire clair; ...de matériaux et couleurs = Gris lumière
Enveloppe 426821 | Niveau 1 | Enveloppe | 426821 | 366 | 9000 | 1908701706 | 1977773087 | 1 | 1 | 0732 | 04 | Niveau 1 | no | rectangle | 161.68 | 376.102 | 0.0128504 | 179.953 | 376.102 | 359.953 | HAUT Niveau 1 (Niveau 2 13545) | 6.75016e-12 | <aucun> | Niveau 1 (Niveau 1 2343) | 161.7 | 161.7 | 376.1 | 376.1 | 2400 | 2400 | 2400 | 60800 | 910000 | Gris lumière | Ivoire clair | 912123 | 482056 | 15 | 376.102 | 2425.2 | 60808.2 | 32137 | ...de stratigraphies = default; ...de matériaux et couleurs - 1 = Ivoire clair; ...de matériaux et couleurs - 2 = Ivoire clair; ...de matériaux et couleurs = Gris lumière
Enveloppe 440399 | Niveau 1 | Enveloppe | 440399 | 366 | 9000 | 1908701706 | 1977773087 | 1 | 1 | 0736 | 04 | Niveau 1 | no | rectangle | 208.859 | 376.102 | 0.0128504 | 89.8152 | 376.102 | 269.815 | HAUT Niveau 1 (Niveau 2 13545) | 6.75016e-12 | <aucun> | Niveau 1 (Niveau 1 2343) | 208.9 | 208.9 | 376.1 | 376.1 | 3100 | 3100 | 3100 | 78600 | 1180000 | Gris lumière | Ivoire clair | 1178284 | 776974 | 15 | 376.102 | 3132.88 | 78552.3 | 51798.3 | ...de stratigraphies = default; ...de matériaux et couleurs - 1 = Ivoire clair; ...de matériaux et couleurs - 2 = Ivoire clair; ...de matériaux et couleurs = Gris lumière
Enveloppe 440747 | Niveau 1 | Enveloppe | 440747 | 366 | 9000 | 1908701706 | 1977773087 | 1 | 1 | 0737 | 04 | Niveau 1 | no | rectangle | 24.8537 | 376.102 | 0.0128504 | 43.1073 | 376.102 | 223.107 | HAUT Niveau 1 (Niveau 2 13545) | 6.75016e-12 | <aucun> | Niveau 1 (Niveau 1 2343) | 24.9 | 24.9 | 376.1 | 376.1 | 400 | 400 | 400 | 9400 | 140000 | Gris lumière | Ivoire clair | 140213 | 140213 | 15 | 376.102 | 372.805 | 9347.52 | 9347.52 | ...de stratigraphies = default; ...de matériaux et couleurs - 1 = Ivoire clair; ...de matériaux et couleurs - 2 = Ivoire clair; ...de matériaux et couleurs = Gris lumière
Enveloppe 426396 | Niveau 1 | Enveloppe | 426396 | 366 | 9000 | 1908701706 | 1977773087 | 1 | 1 | 0725 | 04 | Niveau 1 | no | rectangle | 24.3169 | 376.102 | 0.0128504 | 89.9289 | 376.102 | 269.929 | HAUT Niveau 1 (Niveau 2 13545) | 6.75016e-12 | <aucun> | Niveau 1 (Niveau 1 2343) | 24.3 | 24.3 | 376.1 | 376.1 | 400 | 400 | 400 | 9100 | 140000 | Gris lumière | Ivoire clair | 137185 | 137185 | 15 | 376.102 | 364.754 | 9145.65 | 9145.65 | ...de stratigraphies = default; ...de matériaux et couleurs - 1 = Ivoire clair; ...de matériaux et couleurs - 2 = Ivoire clair; ...de matériaux et couleurs = Gris lumière
Enveloppe 426162 | Niveau 1 | Enveloppe | 426162 | 366 | 9000 | 1908701706 | 1977773087 | 0 | 1 | 0722 | 04 | Niveau 1 | no | rectangle | 155.03 | 376.102 | 0.0128504 | 179.781 | 376.102 | 359.781 | HAUT Niveau 1 (Niveau 2 13545) | 6.75016e-12 | <aucun> | Niveau 1 (Niveau 1 2343) | 155 | 155 | 376.1 | 376.1 | 2300 | 2300 | 2300 | 58300 | 870000 | Gris lumière | Ivoire clair | 874609 | 389243 | 15 | 376.102 | 2325.45 | 58307.2 | 25949.6 | ...de stratigraphies = default; ...de matériaux et couleurs - 1 = Ivoire clair; ...de matériaux et couleurs - 2 = Ivoire clair; ...de matériaux et couleurs = Gris lumière
Enveloppe 426248 | Niveau 1 | Enveloppe | 426248 | 366 | 9000 | 1908701706 | 1977773087 | 1 | 1 | 0723 | 04 | Niveau 1 | no | rectangle | 305.184 | 376.102 | 0.0128504 | 0.119595 | 376.102 | 180.12 | HAUT Niveau 1 (Niveau 2 13545) | 6.75016e-12 | <aucun> | Niveau 1 (Niveau 1 2343) | 305.2 | 305.2 | 376.1 | 376.1 | 4600 | 4600 | 4600 | 114800 | 1720000 | Gris lumière | Ivoire clair | 1721706 | 697896 | 15 | 376.102 | 4577.76 | 114780 | 46526.4 | ...de stratigraphies = default; ...de matériaux et couleurs - 1 = Ivoire clair; ...de matériaux et couleurs - 2 = Ivoire clair; ...de matériaux et couleurs = Gris lumière
Enveloppe 426398 | Niveau 1 | Enveloppe | 426398 | 366 | 9000 | 1908701706 | 1977773087 | 1 | 1 | 0726 | 04 | Niveau 1 | no | rectangle | 50.219 | 376.102 | 0.0128504 | 90.3425 | 376.102 | 270.343 | HAUT Niveau 1 (Niveau 2 13545) | 6.75016e-12 | <aucun> | Niveau 1 (Niveau 1 2343) | 50.2 | 50.2 | 376.1 | 376.1 | 800 | 800 | 800 | 18900 | 280000 | Gris lumière | Ivoire clair | 283312 | 283312 | 15 | 376.102 | 753.284 | 18887.5 | 18887.5 | ...de stratigraphies = default; ...de matériaux et couleurs - 1 = Ivoire clair; ...de matériaux et couleurs - 2 = Ivoire clair; ...de matériaux et couleurs = Gris lumière
Enveloppe 426578 | Niveau 1 | Enveloppe | 426578 | 366 | 9000 | 1908701706 | 1977773087 | 1 | 1 | 0729 | 04 | Niveau 1 | no | rectangle | 312.598 | 376.102 | 0.0128504 | 179.841 | 376.102 | 359.841 | HAUT Niveau 1 (Niveau 2 13545) | 6.75016e-12 | <aucun> | Niveau 1 (Niveau 1 2343) | 312.6 | 312.6 | 376.1 | 376.1 | 4700 | 4700 | 4700 | 117600 | 1760000 | Gris lumière | Ivoire clair | 1763533 | 902969 | 15 | 376.102 | 4688.97 | 117569 | 60197.9 | ...de stratigraphies = default; ...de matériaux et couleurs - 1 = Ivoire clair; ...de matériaux et couleurs - 2 = Ivoire clair; ...de matériaux et couleurs = Gris lumière
Enveloppe 426696 | Niveau 1 | Enveloppe | 426696 | 366 | 9000 | 1908701706 | 1977773087 | 1 | 1 | 0730 | 04 | Niveau 1 | no | rectangle | 232.195 | 376.102 | 0.0128504 | 179.869 | 376.102 | 359.869 | HAUT Niveau 1 (Niveau 2 13545) | 6.75016e-12 | <aucun> | Niveau 1 (Niveau 1 2343) | 232.2 | 232.2 | 376.1 | 376.1 | 3500 | 3500 | 3500 | 87300 | 1310000 | Gris lumière | Ivoire clair | 1309938 | 745291 | 15 | 376.102 | 3482.93 | 87329.2 | 49686 | ...de stratigraphies = default; ...de matériaux et couleurs - 1 = Ivoire clair; ...de matériaux et couleurs - 2 = Ivoire clair; ...de matériaux et couleurs = Gris lumière
Enveloppe 426428 | Niveau 1 | Enveloppe | 426428 | 366 | 9000 | 1908701706 | 1977773087 | 1 | 1 | 0727 | 04 | Niveau 1 | no | rectangle | 60.3023 | 376.102 | 0.0128504 | 0.130126 | 376.102 | 180.13 | HAUT Niveau 1 (Niveau 2 13545) | 6.75016e-12 | <aucun> | Niveau 1 (Niveau 1 2343) | 60.3 | 60.3 | 376.1 | 376.1 | 900 | 900 | 900 | 22700 | 340000 | Gris lumière | Ivoire clair | 340197 | 340197 | 15 | 376.102 | 904.535 | 22679.8 | 22679.8 | ...de stratigraphies = default; ...de matériaux et couleurs - 1 = Ivoire clair; ...de matériaux et couleurs - 2 = Ivoire clair; ...de matériaux et couleurs = Gris lumière
Enveloppe 426493 | Niveau 1 | Enveloppe | 426493 | 366 | 9000 | 1908701706 | 1977773087 | 1 | 1 | 0728 | 04 | Niveau 1 | no | rectangle | 159.426 | 376.102 | 0.0128504 | 89.8082 | 376.102 | 269.808 | HAUT Niveau 1 (Niveau 2 13545) | 6.75016e-12 | <aucun> | Niveau 1 (Niveau 1 2343) | 159.4 | 159.4 | 376.1 | 376.1 | 2400 | 2400 | 2400 | 60000 | 900000 | Gris lumière | Ivoire clair | 899406 | 476990 | 15 | 376.102 | 2391.39 | 59960.4 | 31799.4 | ...de stratigraphies = default; ...de matériaux et couleurs - 1 = Ivoire clair; ...de matériaux et couleurs - 2 = Ivoire clair; ...de matériaux et couleurs = Gris lumière
Enveloppe 1669882 | Niveau 1 | Enveloppe | 1669882 | 366 | 9000 | 1977773087 | 1977773087 | 1 | 1 | 1165 | 04 | Niveau 1 | no | rectangle | 203.336 | 27.8 | 213 | 89.4305 | 27.8 | 269.431 | HAUT Niveau 1 (Niveau 2 13545) | -135.315 | <aucun> | Niveau 1 (Niveau 1 2343) | 203.3 | 203.3 | 27.8 | 27.8 | 3000 | 3000 | 3000 | 5700 | 90000 | Ivoire clair | Ivoire clair | 84790.9 | 84790.9 | 15 | 27.8 | 3050.03 | 5652.73 | 5652.73 | ...de stratigraphies = default; ...de matériaux et couleurs = Ivoire clair; ...de matériaux et couleurs - 1 = Ivoire clair; ...de matériaux et couleurs - 2 = Ivoire clair
Enveloppe 1686694 | Niveau 1 | Enveloppe | 1686694 | 366 | 9000 | 1977773087 | 1977773087 | 0 | 1 | 1168 | 04 | Niveau 1 | no | rectangle | 305.159 | 36 | 128 | 150.569 | 36 | 330.569 | HAUT Niveau 1 (Niveau 2 13545) | -212.115 | <aucun> | Niveau 1 (Niveau 1 2343) | 305.2 | 305.2 | 36 | 36 | 4600 | 4600 | 4600 | 11000 | 170000 | Ivoire clair | Ivoire clair | 164786 | 164786 | 15 | 36 | 4577.39 | 10985.7 | 10985.7 | ...de stratigraphies = default; ...de matériaux et couleurs = Ivoire clair; ...de matériaux et couleurs - 1 = Ivoire clair; ...de matériaux et couleurs - 2 = Ivoire clair
Enveloppe 1696959 | Niveau 1 | Enveloppe | 1696959 | 366 | 9000 | 1977773087 | 1977773087 | 0 | 1 | 1169 | 04 | Niveau 1 | no | rectangle | 36.7535 | 36 | 128 | 90.0993 | 36 | 270.099 | HAUT Niveau 1 (Niveau 2 13545) | -212.115 | <aucun> | Niveau 1 (Niveau 1 2343) | 36.8 | 36.8 | 36 | 36 | 600 | 600 | 600 | 1300 | 20000 | Ivoire clair | Ivoire clair | 19846.9 | 19846.9 | 15 | 36 | 551.303 | 1323.13 | 1323.13 | ...de stratigraphies = default; ...de matériaux et couleurs = Ivoire clair; ...de matériaux et couleurs - 1 = Ivoire clair; ...de matériaux et couleurs - 2 = Ivoire clair
Enveloppe 1679334 | Niveau 1 | Enveloppe | 1679334 | 366 | 9000 | 1977773087 | 1977773087 | 1 | 1 | 1166 | 04 | Niveau 1 | no | rectangle | 204.361 | 22 | 66 | 90.0947 | 22 | 270.095 | HAUT Niveau 1 (Niveau 2 13545) | -288.115 | <aucun> | Niveau 1 (Niveau 1 2343) | 204.4 | 204.4 | 22 | 22 | 3100 | 3100 | 3100 | 4500 | 70000 | Ivoire clair | Ivoire clair | 67439 | 67439 | 15 | 22 | 3065.41 | 4495.93 | 4495.93 | ...de stratigraphies = default; ...de matériaux et couleurs = Ivoire clair; ...de matériaux et couleurs - 1 = Ivoire clair; ...de matériaux et couleurs - 2 = Ivoire clair
Enveloppe 1686645 | Niveau 1 | Enveloppe | 1686645 | 366 | 9000 | 1977773087 | 1977773087 | 0 | 1 | 1167 | 04 | Niveau 1 | no | rectangle | 307.244 | 36 | 128 | 29.28 | 36 | 209.28 | HAUT Niveau 1 (Niveau 2 13545) | -212.115 | <aucun> | Niveau 1 (Niveau 1 2343) | 307.2 | 307.2 | 36 | 36 | 4600 | 4600 | 4600 | 11100 | 170000 | Ivoire clair | Ivoire clair | 165912 | 165912 | 15 | 36 | 4608.65 | 11060.8 | 11060.8 | ...de stratigraphies = default; ...de matériaux et couleurs = Ivoire clair; ...de matériaux et couleurs - 1 = Ivoire clair; ...de matériaux et couleurs - 2 = Ivoire clair
Enveloppe 94889 | Niveau 1 | Enveloppe | 94889 | 366 | 9000 | 1977773087 | 1977773087 | 1 | 0 | 0240 | 04 | Niveau 1 | no | rectangle | 55.8899 | 376.102 | 0.0128504 | 90.2628 | 376.102 | 270.263 | HAUT Niveau 1 (Niveau 2 13545) | 7.10543e-13 | <aucun> | Niveau 1 (Niveau 1 2343) | 55.9 | 55.9 | 376.1 | 376.1 | 800 | 800 | 800 | 21000 | 320000 | Ivoire clair | Ivoire clair | 315305 | 315305 | 15 | 376.102 | 838.348 | 21020.3 | 21020.3 | ...de stratigraphies = default; ...de matériaux et couleurs = Ivoire clair; ...de matériaux et couleurs - 1 = Ivoire clair; ...de matériaux et couleurs - 2 = Ivoire clair
Enveloppe 426311 | Niveau 1 | Enveloppe | 426311 | 366 | 9000 | 1908701706 | 1977773087 | 1 | 1 | 0724 | 04 | Niveau 1 | no | rectangle | 360.188 | 376.102 | 0.0128504 | 89.8106 | 376.102 | 269.811 | HAUT Niveau 1 (Niveau 2 13545) | 6.75016e-12 | <aucun> | Niveau 1 (Niveau 1 2343) | 360.1 | 360.1 | 376.1 | 376.1 | 5300 | 5300 | 5300 | 135400 | 2030000 | Gris lumière | Ivoire clair | 2032010 | 1513073 | 15 | 376.102 | 5402.81 | 135467 | 100872 | ...de stratigraphies = default; ...de matériaux et couleurs - 1 = Ivoire clair; ...de matériaux et couleurs - 2 = Ivoire clair; ...de matériaux et couleurs = Gris lumière
Enveloppe 466473 | Niveau 2 | Enveloppe | 466473 | 366 | 9000 | 1977773087 | 1977773087 | 1 | 1 | 0809 | 05 | Niveau 2 | no | trapèze | 29.4008 | 256.096 | -1.95399e-11 | 90.1529 | 262.568 | 270.153 | Couverture (Couverture 2134) | 0 | Toit782750 | Niveau 2 (Niveau 2 13545) | 29.4 | 30.1 | 262.6 | 256.1 | 400 | 400 | 500 | 7700 | 120000 | Ivoire clair | Ivoire clair | 115597 | 115597 | 15 | 262.117 | 441.012 | 7706.47 | 7706.47 | ...de stratigraphies = default; ...de matériaux et couleurs = Ivoire clair; ...de matériaux et couleurs - 1 = Ivoire clair; ...de matériaux et couleurs - 2 = Ivoire clair
Enveloppe 460240 | Niveau 2 | Enveloppe | 460240 | 366 | 9000 | 1977773087 | 1977773087 | 1 | 1 | 0757 | 05 | Niveau 2 | no | rectangle | 144.461 | 265.062 | -1.95399e-11 | 45.5479 | 265.062 | 225.548 | Couverture (Couverture 2134) | -249.641 | <aucun> | Niveau 2 (Niveau 2 13545) | 144.5 | 144.5 | 265.1 | 265.1 | 2200 | 2200 | 2200 | 38300 | 570000 | Ivoire clair | Ivoire clair | 574365 | 290342 | 15 | 265.062 | 2166.91 | 38291 | 19356.2 | ...de stratigraphies = default; ...de matériaux et couleurs = Ivoire clair; ...de matériaux et couleurs - 1 = Ivoire clair; ...de matériaux et couleurs - 2 = Ivoire clair
Enveloppe 460516 | Niveau 2 | Enveloppe | 460516 | 366 | 9000 | 1977773087 | 1977773087 | 1 | 1 | 0758 | 05 | Niveau 2 | no | trapèze | 29.4447 | 255.703 | -1.95399e-11 | 44.8748 | 259.228 | 224.875 | Couverture (Couverture 2134) | 0 | Toit782750 | Niveau 2 (Niveau 2 13545) | 29.4 | 29.6 | 259.2 | 255.7 | 400 | 400 | 400 | 7600 | 110000 | Ivoire clair | Ivoire clair | 113715 | 113715 | 15 | 257.466 | 441.67 | 7581 | 7581 | ...de stratigraphies = default; ...de matériaux et couleurs = Ivoire clair; ...de matériaux et couleurs - 1 = Ivoire clair; ...de matériaux et couleurs - 2 = Ivoire clair
Enveloppe 461843 | Niveau 2 | Enveloppe | 461843 | 366 | 9000 | 1977773087 | 1977773087 | 0 | 1 | 0770 | 05 | Niveau 2 | no | rectangle | 29.8797 | 235 | -1.95399e-11 | 135.126 | 235 | 315.126 | HAUT Niveau 2 (Mezzanine 49003) | 1.75859e-11 | <aucun> | Niveau 2 (Niveau 2 13545) | 29.9 | 29.9 | 235 | 235 | 400 | 400 | 400 | 7000 | 110000 | Ivoire clair | Ivoire clair | 105326 | 105326 | 15 | 235 | 448.196 | 7021.73 | 7021.73 | ...de stratigraphies = default; ...de matériaux et couleurs = Ivoire clair; ...de matériaux et couleurs - 1 = Ivoire clair; ...de matériaux et couleurs - 2 = Ivoire clair
Enveloppe 461612 | Niveau 2 | Enveloppe | 461612 | 366 | 9000 | 1977773087 | 1977773087 | 0 | 1 | 0768 | 05 | Niveau 2 | no | rectangle | 24.4008 | 235 | 6.75016e-12 | 135.126 | 235 | 315.126 | HAUT Niveau 2 (Mezzanine 49003) | 1.65201e-11 | <aucun> | Niveau 2 (Niveau 2 13545) | 24.4 | 24.4 | 235 | 235 | 400 | 400 | 400 | 5700 | 90000 | Ivoire clair | Ivoire clair | 86012.7 | 86012.7 | 15 | 235 | 366.012 | 5734.18 | 5734.18 | ...de stratigraphies = default; ...de matériaux et couleurs = Ivoire clair; ...de matériaux et couleurs - 1 = Ivoire clair; ...de matériaux et couleurs - 2 = Ivoire clair
Enveloppe 461744 | Niveau 2 | Enveloppe | 461744 | 366 | 9000 | 1977773087 | 1977773087 | 0 | 1 | 0769 | 05 | Niveau 2 | no | rectangle | 144.902 | 265.062 | -1.95399e-11 | 135.126 | 265.062 | 315.126 | Couverture (Couverture 2134) | -249.641 | <aucun> | Niveau 2 (Niveau 2 13545) | 144.9 | 144.9 | 265.1 | 265.1 | 2200 | 2200 | 2200 | 38400 | 580000 | Ivoire clair | Ivoire clair | 576120 | 285979 | 15 | 265.062 | 2173.53 | 38408 | 19065.3 | ...de stratigraphies = default; ...de matériaux et couleurs = Ivoire clair; ...de matériaux et couleurs - 1 = Ivoire clair; ...de matériaux et couleurs - 2 = Ivoire clair
Enveloppe 460913 | Niveau 2 | Enveloppe | 460913 | 366 | 9000 | 1977773087 | 1977773087 | 1 | 1 | 0761 | 05 | Niveau 2 | no | rectangle | 20.7728 | 254.622 | -1.95399e-11 | 89.8106 | 254.622 | 269.811 | Couverture (Couverture 2134) | -260.081 | <aucun> | Niveau 2 (Niveau 2 13545) | 20.8 | 20.8 | 254.6 | 254.6 | 300 | 300 | 300 | 5300 | 80000 | Ivoire clair | Ivoire clair | 79338.1 | 79338.1 | 15 | 254.622 | 311.592 | 5289.2 | 5289.2 | ...de stratigraphies = default; ...de matériaux et couleurs = Ivoire clair; ...de matériaux et couleurs - 1 = Ivoire clair; ...de matériaux et couleurs - 2 = Ivoire clair
Enveloppe 461013 | Niveau 2 | Enveloppe | 461013 | 366 | 9000 | 1977773087 | 1977773087 | 1 | 1 | 0762 | 05 | Niveau 2 | no | rectangle | 34.1376 | 254.622 | -1.95399e-11 | 89.9289 | 254.622 | 269.929 | Couverture (Couverture 2134) | -260.081 | <aucun> | Niveau 2 (Niveau 2 13545) | 34.1 | 34.1 | 254.6 | 254.6 | 500 | 500 | 500 | 8700 | 130000 | Ivoire clair | Ivoire clair | 130383 | 130383 | 15 | 254.622 | 512.064 | 8692.17 | 8692.17 | ...de stratigraphies = default; ...de matériaux et couleurs = Ivoire clair; ...de matériaux et couleurs - 1 = Ivoire clair; ...de matériaux et couleurs - 2 = Ivoire clair
Enveloppe 460749 | Niveau 2 | Enveloppe | 460749 | 366 | 9000 | 1977773087 | 1977773087 | 1 | 1 | 0760 | 05 | Niveau 2 | no | rectangle | 289.378 | 255.509 | -1.95399e-11 | 0.119595 | 255.509 | 180.12 | HAUT Niveau 2 (Mezzanine 49003) | 20.5086 | <aucun> | Niveau 2 (Niveau 2 13545) | 289.4 | 289.4 | 255.5 | 255.5 | 4300 | 4300 | 4300 | 73900 | 1110000 | Ivoire clair | Ivoire clair | 1109079 | 528883 | 15 | 255.509 | 4340.67 | 73938.6 | 35258.9 | ...de stratigraphies = default; ...de matériaux et couleurs = Ivoire clair; ...de matériaux et couleurs - 1 = Ivoire clair; ...de matériaux et couleurs - 2 = Ivoire clair
Enveloppe 461114 | Niveau 2 | Enveloppe | 461114 | 366 | 9000 | 1977773087 | 1977773087 | 1 | 1 | 0763 | 05 | Niveau 2 | no | rectangle | 50.0053 | 245 | -1.95399e-11 | 90.3425 | 245 | 270.343 | HAUT Niveau 2 (Mezzanine 49003) | 10 | <aucun> | Niveau 2 (Niveau 2 13545) | 50 | 50 | 245 | 245 | 800 | 800 | 800 | 12300 | 180000 | Ivoire clair | Ivoire clair | 183769 | 183769 | 15 | 245 | 750.079 | 12251.3 | 12251.3 | ...de stratigraphies = default; ...de matériaux et couleurs = Ivoire clair; ...de matériaux et couleurs - 1 = Ivoire clair; ...de matériaux et couleurs - 2 = Ivoire clair
Enveloppe 461412 | Niveau 2 | Enveloppe | 461412 | 366 | 9000 | 1977773087 | 1977773087 | 1 | 1 | 0766 | 05 | Niveau 2 | no | rectangle | 142.334 | 255 | -1.95399e-11 | 179.721 | 255 | 359.721 | HAUT Niveau 2 (Mezzanine 49003) | 20 | <aucun> | Niveau 2 (Niveau 2 13545) | 142.3 | 142.3 | 255 | 255 | 2100 | 2100 | 2100 | 36300 | 540000 | Ivoire clair | Ivoire clair | 544427 | 265883 | 15 | 255 | 2135.01 | 36295.1 | 17725.6 | ...de stratigraphies = default; ...de matériaux et couleurs = Ivoire clair; ...de matériaux et couleurs - 1 = Ivoire clair; ...de matériaux et couleurs - 2 = Ivoire clair
Enveloppe 461511 | Niveau 2 | Enveloppe | 461511 | 366 | 9000 | 1977773087 | 1977773087 | 0 | 1 | 0767 | 05 | Niveau 2 | no | rectangle | 263.603 | 265.062 | -1.95399e-11 | 89.9552 | 265.062 | 269.955 | HAUT Mezzanine (Couverture 2134) | -249.641 | <aucun> | Niveau 2 (Niveau 2 13545) | 263.6 | 263.6 | 265.1 | 265.1 | 4000 | 4000 | 4000 | 69900 | 1050000 | Ivoire clair | Ivoire clair | 1048066 | 549004 | 15 | 265.062 | 3954.04 | 69871 | 36600.3 | ...de stratigraphies = default; ...de matériaux et couleurs = Ivoire clair; ...de matériaux et couleurs - 1 = Ivoire clair; ...de matériaux et couleurs - 2 = Ivoire clair
Enveloppe 461213 | Niveau 2 | Enveloppe | 461213 | 366 | 9000 | 1977773087 | 1977773087 | 1 | 1 | 0764 | 05 | Niveau 2 | no | rectangle | 145.969 | 235 | -1.95399e-11 | 89.8082 | 235 | 269.808 | HAUT Niveau 2 (Mezzanine 49003) | 1.61648e-11 | <aucun> | Niveau 2 (Niveau 2 13545) | 146 | 146 | 235 | 235 | 2200 | 2200 | 2200 | 34300 | 510000 | Ivoire clair | Ivoire clair | 514542 | 229813 | 15 | 235 | 2189.54 | 34302.8 | 15320.9 | ...de stratigraphies = default; ...de matériaux et couleurs = Ivoire clair; ...de matériaux et couleurs - 1 = Ivoire clair; ...de matériaux et couleurs - 2 = Ivoire clair
Enveloppe 461312 | Niveau 2 | Enveloppe | 461312 | 366 | 9000 | 1977773087 | 1977773087 | 1 | 1 | 0765 | 05 | Niveau 2 | no | rectangle | 20.4671 | 235 | -1.95399e-11 | 179.855 | 235 | 359.855 | HAUT Niveau 2 (Mezzanine 49003) | 1.61648e-11 | <aucun> | Niveau 2 (Niveau 2 13545) | 20.5 | 20.5 | 235 | 235 | 300 | 300 | 300 | 4800 | 70000 | Ivoire clair | Ivoire clair | 72146.6 | 72146.6 | 15 | 235 | 307.007 | 4809.77 | 4809.77 | ...de stratigraphies = default; ...de matériaux et couleurs = Ivoire clair; ...de matériaux et couleurs - 1 = Ivoire clair; ...de matériaux et couleurs - 2 = Ivoire clair
Enveloppe 471093 | Niveau 2 | Enveloppe | 471093 | 366 | 9000 | 1977773087 | 1977773087 | 0 | 0 | 0831 | 05 | Niveau 2 | no | rectangle | 370.634 | 215 | 1.42109e-12 | 0.436421 | 215 | 180.436 | HAUT Niveau 2 (Mezzanine 49003) | -20 | <aucun> | Niveau 2 (Niveau 2 13545) | 370.6 | 370.6 | 215 | 215 | 5600 | 5600 | 5600 | 79700 | 1200000 | Ivoire clair | Ivoire clair | 1195294 | 1195294 | 15 | 215 | 5559.51 | 79686.3 | 79686.3 | ...de stratigraphies = default; ...de matériaux et couleurs = Ivoire clair; ...de matériaux et couleurs - 1 = Ivoire clair; ...de matériaux et couleurs - 2 = Ivoire clair
Enveloppe 470975 | Niveau 2 | Enveloppe | 470975 | 366 | 9000 | 1977773087 | 1977773087 | 0 | 0 | 0830 | 05 | Niveau 2 | no | trapèze | 29.9138 | 260.192 | 1.42109e-12 | 45.0217 | 255.972 | 225.022 | Couverture (Couverture 2134) | 0 | Toit782750 | Niveau 2 (Niveau 2 13545) | 29.9 | 30.2 | 260.2 | 256 | 400 | 400 | 500 | 7700 | 120000 | Ivoire clair | Ivoire clair | 115803 | 115803 | 15 | 258.082 | 448.706 | 7720.21 | 7720.21 | ...de stratigraphies = default; ...de matériaux et couleurs = Ivoire clair; ...de matériaux et couleurs - 1 = Ivoire clair; ...de matériaux et couleurs - 2 = Ivoire clair
Enveloppe 744796 | Niveau 2 | Enveloppe | 744796 | 366 | 9000 | 1977773087 | 1977773087 | 0 | 1 | 1085 | 05 | Niveau 2 | no | rectangle | 142.892 | 246.742 | -1.95399e-11 | 89.9479 | 246.742 | 269.948 | HAUT Niveau 2 (Mezzanine 49003) | 11.742 | <aucun> | Niveau 2 (Niveau 2 13545) | 142.9 | 142.9 | 246.7 | 246.7 | 2100 | 2100 | 2100 | 35300 | 530000 | Ivoire clair | Ivoire clair | 528860 | 235273 | 15 | 246.742 | 2143.37 | 35257.4 | 15684.9 | ...de stratigraphies = default; ...de matériaux et couleurs = Ivoire clair; ...de matériaux et couleurs - 1 = Ivoire clair; ...de matériaux et couleurs - 2 = Ivoire clair
Enveloppe 748512 | Niveau 2 | Enveloppe | 748512 | 366 | 9000 | 1977773087 | 1977773087 | 0 | 0 | 1086 | 05 | Niveau 2 | no | rectangle | 192.351 | 215 | 1.42109e-12 | 90.1529 | 215 | 270.153 | HAUT Niveau 2 (Mezzanine 49003) | -20 | <aucun> | Niveau 2 (Niveau 2 13545) | 192.4 | 192.4 | 215 | 215 | 2900 | 2900 | 2900 | 41400 | 620000 | Ivoire clair | Ivoire clair | 620332 | 620332 | 15 | 215 | 2885.27 | 41355.5 | 41355.5 | ...de stratigraphies = default; ...de matériaux et couleurs = Ivoire clair; ...de matériaux et couleurs - 1 = Ivoire clair; ...de matériaux et couleurs - 2 = Ivoire clair
Enveloppe 748554 | Niveau 2 | Enveloppe | 748554 | 366 | 9000 | 1977773087 | 1977773087 | 0 | 0 | 1087 | 05 | Niveau 2 | no | trapèze | 519.261 | 235 | 1.42109e-12 | 179.781 | 217.941 | 359.781 | HAUT Niveau 2 (Mezzanine 49003) | 0 | <aucun> | Niveau 2 (Niveau 2 13545) | 519.3 | 519.6 | 235 | 217.9 | 7800 | 7800 | 8000 | 118100 | 1770000 | Ivoire clair | Ivoire clair | 1772171 | 1196061 | 15 | 227.525 | 7788.91 | 118145 | 79737.4 | ...de stratigraphies = default; ...de matériaux et couleurs = Ivoire clair; ...de matériaux et couleurs - 1 = Ivoire clair; ...de matériaux et couleurs - 2 = Ivoire clair
Enveloppe 748706 | Niveau 2 | Enveloppe | 748706 | 366 | 9000 | 1977773087 | 1977773087 | 0 | 0 | 1089 | 05 | Niveau 2 | no | rectangle | 145.835 | 230 | 1.42109e-12 | 179.781 | 230 | 359.781 | HAUT Niveau 2 (Mezzanine 49003) | -5 | <aucun> | Niveau 2 (Niveau 2 13545) | 145.8 | 145.8 | 230 | 230 | 2200 | 2200 | 2200 | 33500 | 500000 | Ivoire clair | Ivoire clair | 503129 | 365333 | 15 | 230 | 2187.52 | 33541.9 | 24355.6 | ...de stratigraphies = default; ...de matériaux et couleurs = Ivoire clair; ...de matériaux et couleurs - 1 = Ivoire clair; ...de matériaux et couleurs - 2 = Ivoire clair
Enveloppe 730483 | Niveau 2 | Enveloppe | 730483 | 366 | 9000 | 1977773087 | 1977773087 | 0 | 0 | 1070 | 05 | Niveau 2 | no | rectangle | 205.289 | 349.702 | 8.17124e-12 | 90.1814 | 349.702 | 270.181 | HAUT Mezzanine (Couverture 2134) | -165 | <aucun> | Niveau 2 (Niveau 2 13545) | 205.3 | 205.3 | 349.7 | 349.7 | 3100 | 3100 | 3100 | 71800 | 1080000 | Ivoire clair | Ivoire clair | 1076853 | 1076853 | 15 | 349.702 | 3079.34 | 71790.2 | 71790.2 | ...de stratigraphies = default; ...de matériaux et couleurs = Ivoire clair; ...de matériaux et couleurs - 1 = Ivoire clair; ...de matériaux et couleurs - 2 = Ivoire clair
Enveloppe 150043 | Niveau 2 | Enveloppe | 150043 | 366 | 9000 | 1977773087 | 1977773087 | 0 | 0 | 0322 | 05 | Niveau 2 | no | rectangle | 92.6423 | 235 | 1.42109e-12 | 89.4192 | 235 | 269.419 | HAUT Niveau 2 (Mezzanine 49003) | 0 | <aucun> | Niveau 2 (Niveau 2 13545) | 92.6 | 92.6 | 235 | 235 | 1400 | 1400 | 1400 | 21800 | 330000 | Ivoire clair | Ivoire clair | 326564 | 326564 | 15 | 235 | 1389.63 | 21770.9 | 21770.9 | ...de stratigraphies = default; ...de matériaux et couleurs = Ivoire clair; ...de matériaux et couleurs - 1 = Ivoire clair; ...de matériaux et couleurs - 2 = Ivoire clair
Enveloppe 197291 | Mezzanine | Enveloppe | 197291 | 366 | 9000 | -1156274542 | -1156274542 | 0 | 1 | 0493 | 06 | Mezzanine | no | trapèze | 115.473 | 113.592 | 1.06581e-12 | 90.154 | 113.592 | 270.154 | Couverture (Couverture 2134) | 0 | Toit793923 | Mezzanine (Mezzanine 49003) | 115.5 | 115.5 | 113.6 | 113.6 | 1700 | 1700 | 1700 | 13100 | 200000 | Chêne | Chêne | 196752 | 196752 | 15 | 113.592 | 1732.1 | 13116.8 | 13116.8 | ...de matériaux et couleurs = Chêne; ...de stratigraphies = default; ...de matériaux et couleurs - 1 = Chêne; ...de matériaux et couleurs - 2 = Chêne
Enveloppe 197311 | Mezzanine | Enveloppe | 197311 | 366 | 9000 | -1156274542 | -1156274542 | 0 | 1 | 0494 | 06 | Mezzanine | no | trapèze | 123.996 | 113.592 | 1.06581e-12 | 92.9079 | 99.7256 | 272.908 | Couverture (Couverture 2134) | 0 | Toit793923 | Mezzanine (Mezzanine 49003) | 124 | 124.8 | 113.6 | 99.7 | 1900 | 1900 | 2000 | 14500 | 220000 | Chêne | Chêne | 217676 | 217676 | 15 | 117.034 | 1859.94 | 14511.7 | 14511.7 | ...de matériaux et couleurs = Chêne; ...de stratigraphies = default; ...de matériaux et couleurs - 1 = Chêne; ...de matériaux et couleurs - 2 = Chêne
Enveloppe 197218 | Mezzanine | Enveloppe | 197218 | 366 | 9000 | -1156274542 | -1156274542 | 1 | 1 | 0491 | 06 | Mezzanine | no | rectangle | 135.489 | 279.702 | 1.06581e-12 | 0.108363 | 279.702 | 180.108 | HAUT Mezzanine (Couverture 2134) | 7.10543e-13 | <aucun> | Mezzanine (Mezzanine 49003) | 135.5 | 135.5 | 279.7 | 279.7 | 2000 | 2000 | 2000 | 37900 | 570000 | Chêne | Chêne | 568449 | 568449 | 15 | 279.702 | 2032.34 | 37896.6 | 37896.6 | ...de matériaux et couleurs = Chêne; ...de stratigraphies = default; ...de matériaux et couleurs - 1 = Chêne; ...de matériaux et couleurs - 2 = Chêne
Enveloppe 197272 | Mezzanine | Enveloppe | 197272 | 366 | 9000 | -1156274542 | -1156274542 | 0 | 1 | 0492 | 06 | Mezzanine | no | trapèze | 66.7174 | 233.372 | 1.06581e-12 | 3.72681 | 125.556 | 183.727 | Couverture (Couverture 2134) | 0 | Toit793923 | Mezzanine (Mezzanine 49003) | 66.7 | 126.8 | 233.4 | 125.6 | 1000 | 1000 | 1900 | 12000 | 180000 | Chêne | Chêne | 179600 | 179600 | 15 | 179.464 | 1000.76 | 11973.4 | 11973.4 | ...de matériaux et couleurs = Chêne; ...de stratigraphies = default; ...de matériaux et couleurs - 1 = Chêne; ...de matériaux et couleurs - 2 = Chêne
Enveloppe 196749 | Mezzanine | Enveloppe | 196749 | 366 | 9000 | 1977773087 | 1977773087 | 0 | 0 | 0489 | 06 | Mezzanine | no | trapèze | 92.1416 | 368.017 | 1.42109e-12 | 90.4285 | 223.468 | 270.428 | Couverture (Couverture 2134) | 0 | Toit793923 | Mezzanine (Mezzanine 49003) | 92.1 | 171.4 | 368 | 223.5 | 1400 | 1400 | 2600 | 27200 | 410000 | Ivoire clair | Ivoire clair | 408752 | 150362 | 15 | 295.742 | 1382.12 | 27250.1 | 10024.1 | ...de stratigraphies = default; ...de matériaux et couleurs = Ivoire clair; ...de matériaux et couleurs - 1 = Ivoire clair; ...de matériaux et couleurs - 2 = Ivoire clair

# IfcWallStandardCase: default 153, Enveloppe 69280
In: Rez-de-Jardin
Type - Material: <aucun> 15.3 cm
Description: Enveloppe; Group: ...de stratigraphies = default; ...de matériaux et couleurs = Ivoire clair; ...de matériaux et couleurs - 1 = Ivoire clair; ...de matériaux et couleurs - 2 = Ivoire clair
__RECOGNIZE__ - ID: 69280; TPLG: 366; TPLG_OD: 9000; GENERATE: 1
CTLG_EXTERNAL_LINK - 0, DocType: 2; 0, Tag: 0; 0, Crc: 1977773087; 1, DocType: 2; 1, Tag: 100; 1, Crc: 1977773087; 2, DocType: 2; 2, Tag: 200; 2, Crc: 1977773087; 3, DocType: 9; 3, Tag: 0; 3, Crc: 152922019
IFC_PSET_PolygonOffset - polygonOffsetFactor: 2; polygonOffsetUnits: 2
IFC_Pset_Alignment - Alignment: 1
IFC_Pset_Strat_Detail_Align - ExternalFace: 1
IFC_Pset_Caractéristiques - ID: 69280; Numérotation: 0131; Numéro niveau: 02; Titre niveau: Rez-de-Jardin; Stratigraphie: default [153,00]; Épaisseur: 15.3 cm; Épaisseur VARIABLE: no
IFC_Pset_Caractéristiques_FRUIT - Fruit: no; Taille: 0 cm
IFC_Pset_Géométrie - Forme en Élévation: rectangle; Longueur: 206.386 cm; Hauteur: 106.3 cm; Cote: 43.7 cm
IFC_Pset_Géométrie_P1 (POINT initial) - Hauteur: 106.3 cm; Cote: 43.7 cm; Angle XY: 89.8966 deg
IFC_Pset_Géométrie_P2 (POINT final) - Hauteur: 106.3 cm; Cote: 43.7 cm; Angle XY: 269.897 deg
IFC_Pset_Système de Référence Altimétrique_SUPÉRIEUR - NIVEAU: HAUT Rez-de-Jardin (Rez-de-chaussée 1047); delta: -141.4 cm; delta (P1): -141.4 cm; delta (P2): -141.4 cm; sous Niveau: <aucun>
IFC_Pset_Système de Référence Altimétrique_INFÉRIEUR - NIVEAU: Rez-de-Jardin (Rez-de-Jardin 15545); delta: 43.7 cm; delta (P1): 43.7 cm; delta (P2): 43.7 cm; sous Niveau: <aucun>
IFC_Pset_Données Métré - Longueur Pied: 206.4 cm; Longueur Tête: 206.4 cm; Hauteur Maximale: 106.3 cm; Hauteur Minimale: 106.3 cm; Surface en Plan: 3100 cm2; Surface Pied: 3100 cm2; Surface Tête: 3100 cm2; Surface de la Paroi: 21900 cm2; Volume: 330000 cm3
IFC_Pset_Matériaux - Face gauche: Ivoire clair; Face droite: Ivoire clair; Face latérale: Ivoire clair
Pset_WallCommon - Reference: default [153,00] (..\VERTICALES\Default\)
BaseQuantities - GrossVolume: 335664 cm3; NetVolume: 335664 cm3; NominalLength: 206.386 cm; NominalWidth: 15.3 cm; NominalHeight: 106.3 cm; GrossFootprintArea: 3157.71 cm2; NetFootprintArea: 3157.71 cm2; GrossSideArea: 21938.9 cm2; NetSideArea: 21938.9 cm2

# IfcWallStandardCase: default 154, Enveloppe courbe 279892
In: Rez-de-Jardin
Type - Material: <aucun> 15.4 cm
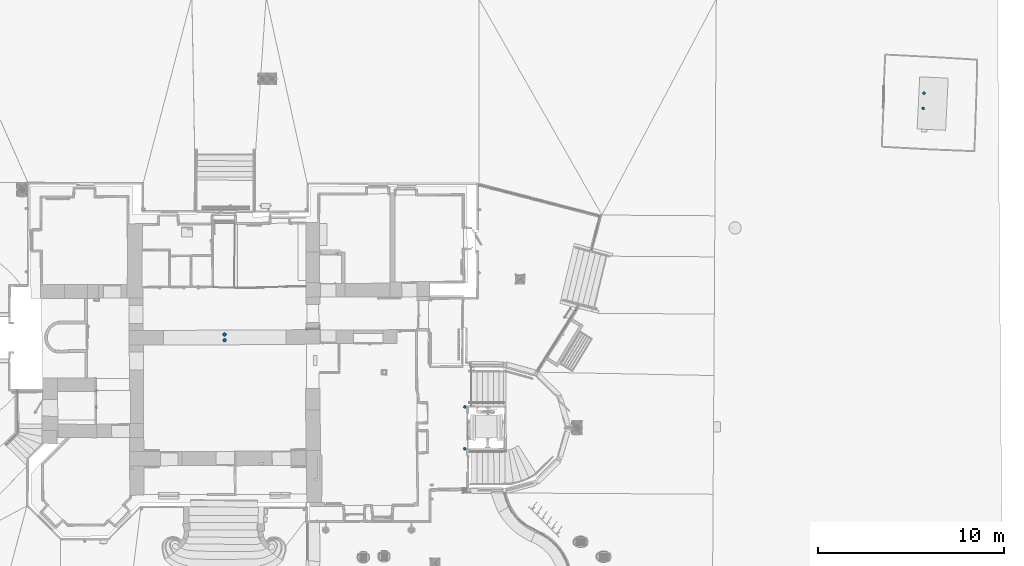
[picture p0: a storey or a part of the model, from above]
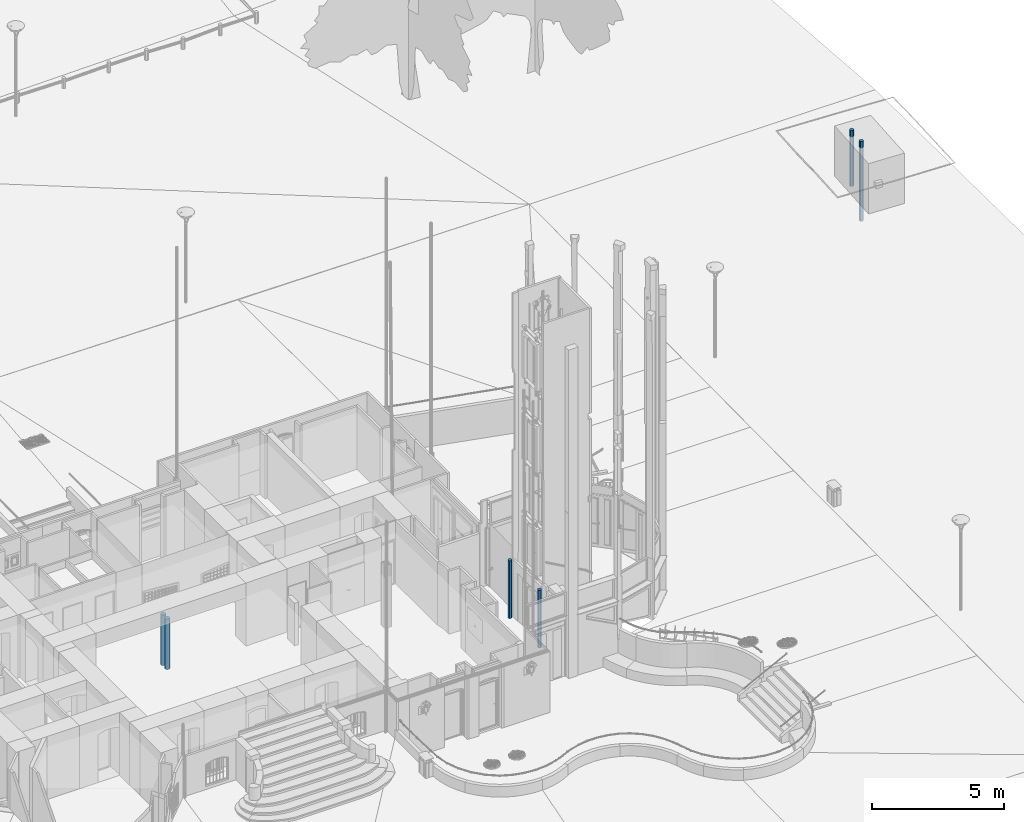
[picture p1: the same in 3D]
Properties of the parts of a building model (IFC2X3), part 22 of 37

# IfcWallStandardCase: default 154, Enveloppe courbe 279892
Description: Enveloppe courbe; Group: ...de matériaux et couleurs = Blanc; ...de matériaux et couleurs - 1 = Blanc; ...de matériaux et couleurs - 2 = Blanc; ...de stratigraphies = default
__RECOGNIZE__ - ID: 279892; TPLG: 367; TPLG_OD: 9001; GENERATE: 1
CTLG_EXTERNAL_LINK - 0, DocType: 2; 0, Tag: 0; 0, Crc: -746779066; 1, DocType: 2; 1, Tag: 100; 1, Crc: -746779066; 2, DocType: 2; 2, Tag: 200; 2, Crc: -746779066; 3, DocType: 9; 3, Tag: 0; 3, Crc: -1807376537
IFC_PSET_PolygonOffset - polygonOffsetFactor: 2; polygonOffsetUnits: 2
IFC_Pset_Alignment - Alignment: 1
IFC_Pset_Strat_Detail_Align - ExternalFace: 0
IFC_Pset_Caractéristiques - ID: 279892; Numérotation: 33; Numéro niveau: 02; Titre niveau: Rez-de-Jardin; Stratigraphie: default [154,00]; Épaisseur: 15.4 cm; Épaisseur VARIABLE: no
IFC_Pset_Caractéristiques_FRUIT - Fruit: no; Taille: 0 cm
IFC_Pset_Géométrie_P1 (POINT initial) - Hauteur: 111 cm; Cote: 43.7 cm; Angle XY: 29.8533 deg
IFC_Pset_Géométrie_P2 (POINT final) - Hauteur: 111 cm; Cote: 43.7 cm; Angle XY: 209.853 deg
IFC_Pset_Géométrie - Rayon: 308.551 cm; Point arc: [1 178,1; -1 885,4] cm; Centre: [1 375,7; -1 658,5] cm; Angle de la Tangente: 10.5236 deg; Forme en Élévation: rectangle; Longueur: 160.767 cm; Hauteur: 111 cm; Cote: 43.7 cm
IFC_Pset_Système de Référence Altimétrique_SUPÉRIEUR - NIVEAU: HAUT Rez-de-Jardin (Rez-de-chaussée 1047); delta: -136.7 cm; delta (P1): -136.7 cm; delta (P2): -136.7 cm; sous Niveau: <aucun>
IFC_Pset_Système de Référence Altimétrique_INFÉRIEUR - NIVEAU: Rez-de-Jardin (Rez-de-Jardin 15545); delta: 43.7 cm; delta (P1): 43.7 cm; delta (P2): 43.7 cm; sous Niveau: <aucun>
IFC_Pset_Données Métré - Longueur Pied: 160.8 cm; Longueur Tête: 160.8 cm; Hauteur Maximale: 111 cm; Hauteur Minimale: 111 cm; Surface en Plan: 1500 cm2; Surface Pied: 2400 cm2; Surface Tête: 2400 cm2; Surface de la Paroi: 17800 cm2; Volume: 270000 cm3
IFC_Pset_Matériaux - Face gauche: Blanc; Face droite: Blanc; Face latérale: Blanc
Pset_WallCommon - Reference: default [154,00] (..\VERTICALES\Default\)
BaseQuantities - GrossVolume: 274285 cm3; NetVolume: 274285 cm3; NominalLength: 160.767 cm; NominalWidth: 15.3703 cm; NominalHeight: 111 cm; GrossFootprintArea: 2471.04 cm2; NetFootprintArea: 2471.04 cm2; GrossSideArea: 17845.1 cm2; NetSideArea: 17845.1 cm2

# IfcWallStandardCase: default 155 (7)
Type - Material: <aucun> 15.5 cm
Description: Enveloppe; Group: ...de stratigraphies = default; ...de matériaux et couleurs = Ivoire clair; ...de matériaux et couleurs - 1 = Ivoire clair; ...de matériaux et couleurs - 2 = Ivoire clair
__RECOGNIZE__ - TPLG: 366; TPLG_OD: 9000; GENERATE: 1
CTLG_EXTERNAL_LINK - 0, DocType: 2; 0, Tag: 0; 0, Crc: 1977773087; 1, DocType: 2; 1, Tag: 100; 1, Crc: 1977773087; 2, DocType: 2; 2, Tag: 200; 2, Crc: 1977773087; 3, DocType: 9; 3, Tag: 0; 3, Crc: 1069906490
IFC_PSET_PolygonOffset - polygonOffsetFactor: 2; polygonOffsetUnits: 2
IFC_Pset_Caractéristiques - Stratigraphie: default [155,00]; Épaisseur: 15.5 cm
IFC_Pset_Caractéristiques_FRUIT - Fruit: no; Taille: 0 cm
IFC_Pset_Système de Référence Altimétrique_SUPÉRIEUR - sous Niveau: <aucun>
IFC_Pset_Matériaux - Face gauche: Ivoire clair; Face droite: Ivoire clair; Face latérale: Ivoire clair
Pset_WallCommon - Reference: default [155,00] (..\VERTICALES\Default\)
Name | In | __RECOGNIZE__, ID = IFC_Pset_Caractéristiques, ID | Alignment | ExternalFace | Numérotation | Numéro niveau | Titre niveau | Épaisseur VARIABLE | Forme en Élévation | Longueur (cm) = NominalLength (cm) | IFC_Pset_Géométrie, Hauteur (cm) = IFC_Pset_Géométrie_P1 (POINT initial), Hauteur (cm) | IFC_Pset_Géométrie, Cote (cm) = IFC_Pset_Géométrie_P1 (POINT initial), Cote (cm) = IFC_Pset_Géométrie_P2 (POINT final), Cote (cm) = IFC_Pset_Système de Référence Altimétrique_INFÉRIEUR, delta (cm) = IFC_Pset_Système de Référence Altimétrique_INFÉRIEUR, delta (P1) (cm) = IFC_Pset_Système de Référence Altimétrique_INFÉRIEUR, delta (P2) (cm) | IFC_Pset_Géométrie_P1 (POINT initial), Angle XY (deg) | IFC_Pset_Géométrie_P2 (POINT final), Hauteur (cm) | IFC_Pset_Géométrie_P2 (POINT final), Angle XY (deg) | IFC_Pset_Système de Référence Altimétrique_SUPÉRIEUR, NIVEAU | IFC_Pset_Système de Référence Altimétrique_SUPÉRIEUR, delta (cm) = IFC_Pset_Système de Référence Altimétrique_SUPÉRIEUR, delta (P1) (cm) = IFC_Pset_Système de Référence Altimétrique_SUPÉRIEUR, delta (P2) (cm) | IFC_Pset_Système de Référence Altimétrique_INFÉRIEUR, NIVEAU | sous Niveau | Longueur Pied (cm) | Longueur Tête (cm) | Hauteur Maximale (cm) | Hauteur Minimale (cm) | Surface en Plan (cm2) = Surface Pied (cm2) | Surface Tête (cm2) | Surface de la Paroi (cm2) | Volume (cm3) | GrossVolume (cm3) | NetVolume (cm3) | NominalWidth (cm) | NominalHeight (cm) | GrossFootprintArea (cm2) = NetFootprintArea (cm2) | GrossSideArea (cm2) | NetSideArea (cm2)
Enveloppe 67656 | Rez-de-Jardin | 67656 | 1 | 1 | 0127 | 02 | Rez-de-Jardin | no | rectangle | 339.215 | 105 | -1.94511e-11 | 90.0631 | 105 | 270.063 | HAUT Rez-de-Jardin (Rez-de-chaussée 1047) | -186.4 | Rez-de-Jardin (Rez-de-Jardin 15545) | <aucun> | 339.2 | 339.2 | 105 | 105 | 5400 | 5400 | 35600 | 570000 | 552072 | 552072 | 15.5 | 105 | 5257.83 | 35617.6 | 35617.6
Enveloppe 295406 | Rez-de-Jardin | 295406 | 1 | 0 | 0535 | 02 | Rez-de-Jardin | no | rectangle | 69.4477 | 156.4 | 8.88178e-14 | 148.611 | 156.4 | 328.611 | HAUT Rez-de-Jardin (Rez-de-chaussée 1047) | -135 | Rez-de-Jardin (Rez-de-Jardin 15545) | <aucun> | 69.4 | 69.4 | 156.4 | 156.4 | 1100 | 1100 | 10900 | 170000 | 168356 | 168356 | 15.5 | 156.4 | 1076.44 | 10861.6 | 10861.6
Enveloppe 295347 | Rez-de-Jardin | 295347 | 1 | 0 | 0534 | 02 | Rez-de-Jardin | no | rectangle | 264.266 | 156.4 | 8.88178e-14 | 58.0648 | 156.4 | 238.065 | HAUT Rez-de-Jardin (Rez-de-chaussée 1047) | -135 | Rez-de-Jardin (Rez-de-Jardin 15545) | <aucun> | 264.3 | 264.3 | 156.4 | 156.4 | 4200 | 4200 | 41300 | 660000 | 640634 | 640634 | 15.5 | 156.4 | 4096.12 | 41331.3 | 41331.3
Enveloppe 134391 | Rez-de-Jardin | 134391 | 0 | 0 | 0310 | 02 | Rez-de-Jardin | no | rectangle | 184.524 | 207.9 | 0 | 75.5162 | 207.9 | 255.516 | HAUT Rez-de-Jardin (Rez-de-chaussée 1047) | -133.5 | Rez-de-Jardin (Rez-de-Jardin 15545) | extérieur | 184.5 | 184.5 | 207.9 | 207.9 | 3000 | 3000 | 38400 | 610000 | 594620 | 594620 | 15.5 | 207.9 | 2860.12 | 38362.6 | 38362.6
Enveloppe 134414 | Rez-de-Jardin | 134414 | 0 | 0 | 0311 | 02 | Rez-de-Jardin | no | rectangle | 666.855 | 207.9 | 0 | 165.476 | 207.9 | 345.476 | HAUT Rez-de-Jardin (Rez-de-chaussée 1047) | -133.5 | Rez-de-Jardin (Rez-de-Jardin 15545) | extérieur | 666.9 | 666.9 | 207.9 | 207.9 | 10700 | 10700 | 138600 | 2220000 | 2148909 | 2148909 | 15.5 | 207.9 | 10336.2 | 138639 | 138639
Enveloppe 134966 | Rez-de-Jardin | 134966 | 0 | 0 | 0312 | 02 | Rez-de-Jardin | yes | trapèze | 88.8495 | 124.997 | 0 | 164.443 | 78.699 | 344.443 | HAUT Rez-de-Jardin (Rez-de-chaussée 1047) | 0 | Rez-de-Jardin (Rez-de-Jardin 15545) | extérieur | 88.8 | 100.1 | 125 | 78.7 | 1400 | 1600 | 9100 | 140000 | 144004 | 144004 | 15.9135 | 101.848 | 1413.91 | 9049.16 | 9049.16
Enveloppe 94649 | Niveau 1 | 94649 | 0 | 0 | 0231 | 04 | Niveau 1 | no | rectangle | 169.896 | 376.102 | 0.0128504 | 136.331 | 376.102 | 316.331 | HAUT Niveau 1 (Niveau 2 13545) | 7.10543e-13 | Niveau 1 (Niveau 1 2343) | <aucun> | 169.9 | 169.9 | 376.1 | 376.1 | 2700 | 2700 | 63900 | 1020000 | 990423 | 730023 | 15.5 | 376.102 | 2633.39 | 63898.3 | 47098.3

# IfcWallStandardCase: default 156 (6)
In: Rez-de-Jardin
Type - Material: <aucun> 15.6 cm
Description: Enveloppe courbe; Group: ...de matériaux et couleurs = Blanc; ...de matériaux et couleurs - 1 = Blanc; ...de matériaux et couleurs - 2 = Blanc; ...de stratigraphies = default
__RECOGNIZE__ - TPLG: 367; TPLG_OD: 9001; GENERATE: 1
CTLG_EXTERNAL_LINK - 0, DocType: 2; 0, Tag: 0; 0, Crc: -746779066; 1, DocType: 2; 1, Tag: 100; 1, Crc: -746779066; 2, DocType: 2; 2, Tag: 200; 2, Crc: -746779066; 3, DocType: 9; 3, Tag: 0; 3, Crc: 74532560
IFC_PSET_PolygonOffset - polygonOffsetFactor: 2; polygonOffsetUnits: 2
IFC_Pset_Strat_Detail_Align - ExternalFace: 0
IFC_Pset_Caractéristiques - Numéro niveau: 02; Titre niveau: Rez-de-Jardin; Stratigraphie: default [156,00]; Épaisseur: 15.6 cm; Épaisseur VARIABLE: no
IFC_Pset_Caractéristiques_FRUIT - Fruit: no; Taille: 0 cm
IFC_Pset_Géométrie_P1 (POINT initial) - Hauteur: 111 cm; Cote: 43.7 cm
IFC_Pset_Géométrie_P2 (POINT final) - Hauteur: 111 cm; Cote: 43.7 cm
IFC_Pset_Géométrie - Forme en Élévation: rectangle; Hauteur: 111 cm; Cote: 43.7 cm
IFC_Pset_Système de Référence Altimétrique_SUPÉRIEUR - NIVEAU: HAUT Rez-de-Jardin (Rez-de-chaussée 1047); delta: -136.7 cm; delta (P1): -136.7 cm; delta (P2): -136.7 cm; sous Niveau: <aucun>
IFC_Pset_Système de Référence Altimétrique_INFÉRIEUR - NIVEAU: Rez-de-Jardin (Rez-de-Jardin 15545); delta: 43.7 cm; delta (P1): 43.7 cm; delta (P2): 43.7 cm; sous Niveau: <aucun>
IFC_Pset_Données Métré - Hauteur Maximale: 111 cm; Hauteur Minimale: 111 cm
IFC_Pset_Matériaux - Face gauche: Blanc; Face droite: Blanc; Face latérale: Blanc
Pset_WallCommon - Reference: default [156,00] (..\VERTICALES\Default\)
BaseQuantities - NominalHeight: 111 cm
Name | __RECOGNIZE__, ID = IFC_Pset_Caractéristiques, ID | Alignment | Numérotation | IFC_Pset_Géométrie_P1 (POINT initial), Angle XY (deg) | IFC_Pset_Géométrie_P2 (POINT final), Angle XY (deg) | Rayon (cm) | Point arc | Centre | Angle de la Tangente (deg) | Longueur (cm) = NominalLength (cm) | Longueur Pied (cm) = Longueur Tête (cm) | Surface en Plan (cm2) | Surface Pied (cm2) = Surface Tête (cm2) | Surface de la Paroi (cm2) | Volume (cm3) | GrossVolume (cm3) = NetVolume (cm3) | NominalWidth (cm) | GrossFootprintArea (cm2) = NetFootprintArea (cm2) | GrossSideArea (cm2) = NetSideArea (cm2)
Enveloppe courbe 282714 | 282714 | 1 | 34 | 19.9661 | 199.966 | 321.397 | [1 102,8; -1 785,4] cm | [1 386,3; -1 651,5] cm | 5.52302 | 111.999 | 112 | 1100 | 1800 | 12400 | 200000 | 193610 | 15.5737 | 1744.23 | 12431.8
Enveloppe courbe 285167 | 285167 | 0 | 37 | 29.2503 | 209.25 | 267.172 | [610,5; -1 593,3] cm | [540,5; -1 343,6] cm | 10.1651 | 136.395 | 136.4 | 1400 | 2200 | 15100 | 240000 | 235695 | 15.5678 | 2123.38 | 15139.9
Enveloppe courbe 284505 | 284505 | 0 | 36 | 48.8887 | 228.889 | 292.277 | [793,3; -1 536,7] cm | [804,3; -1 836,6] cm | 28.9044 | 249.391 | 249.4 | 2500 | 4000 | 27700 | 440000 | 430861 | 15.5645 | 3881.63 | 27682.4
Enveloppe courbe 284085 | 284085 | 1 | 35 | 46.9993 | 226.999 | 287.339 | [1 018,2; -1 626,9] cm | [805,8; -1 831,8] cm | 27.9597 | 235.702 | 235.7 | 2400 | 3800 | 26200 | 420000 | 407206 | 15.5642 | 3668.52 | 26162.9
Enveloppe courbe 285591 | 285591 | 1 | 38 | 56.2051 | 236.205 | 296.069 | [400,8; -1 570,3] cm | [534,3; -1 314,8] cm | 23.6425 | 290.433 | 290.5 | 3000 | 4600 | 32200 | 520000 | 501868 | 15.5675 | 4521.33 | 32238.1
Enveloppe courbe 286107 | 286107 | 1 | 39 | 33.0477 | 213.048 | 302.771 | [262,6; -1 408,3] cm | [542,4; -1 314,6] cm | 12.0638 | 174.636 | 174.7 | 1800 | 2800 | 19400 | 310000 | 301799 | 15.569 | 2718.91 | 19384.5

# IfcWallStandardCase: default 160 (6)
Type - Material: <aucun> 16 cm
Description: Enveloppe
__RECOGNIZE__ - TPLG: 366; TPLG_OD: 9000; GENERATE: 1
CTLG_EXTERNAL_LINK - 0, DocType: 2; 0, Tag: 0; 1, DocType: 2; 1, Tag: 100; 2, DocType: 2; 2, Tag: 200; 3, DocType: 9; 3, Tag: 0; 3, Crc: -1778258999
IFC_PSET_PolygonOffset - polygonOffsetFactor: 2; polygonOffsetUnits: 2
IFC_Pset_Caractéristiques - Stratigraphie: default [160,00]; Épaisseur: 16 cm
IFC_Pset_Caractéristiques_FRUIT - Fruit: no; Taille: 0 cm
IFC_Pset_Système de Référence Altimétrique_INFÉRIEUR - sous Niveau: <aucun>
Pset_WallCommon - Reference: default [160,00] (..\VERTICALES\Default\)
Name | In | __RECOGNIZE__, ID = IFC_Pset_Caractéristiques, ID | 0, Crc = 1, Crc = 2, Crc | Alignment | ExternalFace | Numérotation | Numéro niveau | Titre niveau | Épaisseur VARIABLE | Forme en Élévation | Longueur (cm) = NominalLength (cm) | IFC_Pset_Géométrie, Hauteur (cm) = IFC_Pset_Géométrie_P1 (POINT initial), Hauteur (cm) | IFC_Pset_Géométrie, Cote (cm) = IFC_Pset_Géométrie_P1 (POINT initial), Cote (cm) = IFC_Pset_Géométrie_P2 (POINT final), Cote (cm) = IFC_Pset_Système de Référence Altimétrique_INFÉRIEUR, delta (cm) = IFC_Pset_Système de Référence Altimétrique_INFÉRIEUR, delta (P1) (cm) = IFC_Pset_Système de Référence Altimétrique_INFÉRIEUR, delta (P2) (cm) | IFC_Pset_Géométrie_P1 (POINT initial), Angle XY (deg) | IFC_Pset_Géométrie_P2 (POINT final), Hauteur (cm) | IFC_Pset_Géométrie_P2 (POINT final), Angle XY (deg) | IFC_Pset_Système de Référence Altimétrique_SUPÉRIEUR, NIVEAU | IFC_Pset_Système de Référence Altimétrique_SUPÉRIEUR, delta (cm) = IFC_Pset_Système de Référence Altimétrique_SUPÉRIEUR, delta (P1) (cm) = IFC_Pset_Système de Référence Altimétrique_SUPÉRIEUR, delta (P2) (cm) | sous Niveau | IFC_Pset_Système de Référence Altimétrique_INFÉRIEUR, NIVEAU | Longueur Pied (cm) | Longueur Tête (cm) | Hauteur Maximale (cm) | Hauteur Minimale (cm) | Surface en Plan (cm2) = Surface Pied (cm2) | Surface Tête (cm2) | Surface de la Paroi (cm2) | Volume (cm3) | Face gauche = Face droite = Face latérale | GrossVolume (cm3) = NetVolume (cm3) | NominalWidth (cm) | NominalHeight (cm) | GrossFootprintArea (cm2) = NetFootprintArea (cm2) | GrossSideArea (cm2) = NetSideArea (cm2) | Group
Enveloppe 377554 | Rez-de-chaussée | 377554 | 1977773087 | 0 | 0 | 0660 | 03 | Rez-de-chaussée | no | rectangle | 20.9852 | 477.795 | 0.0128504 | 1.69567 | 477.795 | 181.696 | HAUT Rez-de-chaussée (Niveau 1 2343) | 0.0128504 | <aucun> | Rez-de-chaussée (Rez-de-chaussée 1047) | 21 | 21 | 477.8 | 477.8 | 300 | 300 | 10000 | 160000 | Ivoire clair | 160426 | 16 | 477.795 | 335.764 | 10026.6 | ...de stratigraphies = default; ...de matériaux et couleurs = Ivoire clair; ...de matériaux et couleurs - 1 = Ivoire clair; ...de matériaux et couleurs - 2 = Ivoire clair
Enveloppe 159225 | Niveau 2 | 159225 | 1977773087 | 0 | 0 | 0374 | 05 | Niveau 2 | no | rectangle | 196.887 | 261.846 | 1.42109e-12 | 179.965 | 261.846 | 359.965 | HAUT Niveau 2 (Mezzanine 49003) | 26.8456 | <aucun> | Niveau 2 (Niveau 2 13545) | 196.9 | 196.9 | 261.8 | 261.8 | 3200 | 3200 | 51500 | 820000 | Ivoire clair | 824864 | 16 | 261.846 | 3150.19 | 51554 | ...de stratigraphies = default; ...de matériaux et couleurs = Ivoire clair; ...de matériaux et couleurs - 1 = Ivoire clair; ...de matériaux et couleurs - 2 = Ivoire clair
Enveloppe 196802 | Mezzanine | 196802 | 1977773087 | 0 | 0 | 0490 | 06 | Mezzanine | yes | rectangle | 115.719 | 279.702 | 1.42109e-12 | 136.2 | 279.702 | 316.2 | HAUT Mezzanine (Couverture 2134) | 2.84217e-12 | <aucun> | Mezzanine (Mezzanine 49003) | 115.7 | 115.7 | 279.7 | 279.7 | 1900 | 1900 | 32400 | 520000 | Ivoire clair | 517871 | 16 | 279.702 | 1851.51 | 32366.9 | ...de stratigraphies = default; ...de matériaux et couleurs = Ivoire clair; ...de matériaux et couleurs - 1 = Ivoire clair; ...de matériaux et couleurs - 2 = Ivoire clair
Enveloppe 194053 | Mezzanine | 194053 | -1156274542 | 0 | 1 | 0481 | 06 | Mezzanine | yes | rectangle | 210.972 | 159.702 | 1.06581e-12 | 90.0308 | 159.702 | 270.031 | HAUT Mezzanine (Couverture 2134) | -120 | <aucun> | Mezzanine (Mezzanine 49003) | 211 | 211 | 159.7 | 159.7 | 3500 | 3500 | 33700 | 570000 | Chêne | 561882 | 16.6766 | 159.702 | 3518.3 | 33692.8 | ...de matériaux et couleurs = Chêne; ...de stratigraphies = default; ...de matériaux et couleurs - 1 = Chêne; ...de matériaux et couleurs - 2 = Chêne
Enveloppe 192765 | Mezzanine | 192765 | -1156274542 | 0 | 1 | 0475 | 06 | Mezzanine | no | rectangle | 140.127 | 159.702 | 1.75859e-11 | 90.5824 | 159.702 | 270.582 | HAUT Mezzanine (Couverture 2134) | -120 | <aucun> | Mezzanine (Mezzanine 49003) | 140.1 | 140.1 | 159.7 | 159.7 | 2200 | 2200 | 22400 | 360000 | Chêne | 358058 | 16 | 159.702 | 2242.03 | 22378.6 | ...de matériaux et couleurs = Chêne; ...de stratigraphies = default; ...de matériaux et couleurs - 1 = Chêne; ...de matériaux et couleurs - 2 = Chêne
Enveloppe 194000 | Mezzanine | 194000 | -1156274542 | 1 | 1 | 0480 | 06 | Mezzanine | no | trapèze | 132.402 | 183.534 | 1.06581e-12 | 0.786915 | 118.397 | 180.787 | Couverture (Couverture 2134) | 0 | Toit795368 | Mezzanine (Mezzanine 49003) | 132.4 | 147.5 | 183.5 | 118.4 | 2100 | 2400 | 20000 | 320000 | Chêne | 319809 | 16 | 150.965 | 2118.43 | 19988.1 | ...de matériaux et couleurs = Chêne; ...de stratigraphies = default; ...de matériaux et couleurs - 1 = Chêne; ...de matériaux et couleurs - 2 = Chêne

# IfcWallStandardCase: default 165 (2)
Type - Material: <aucun> 16.5 cm
Description: Enveloppe; Group: ...de stratigraphies = default; ...de matériaux et couleurs = Ivoire clair; ...de matériaux et couleurs - 1 = Ivoire clair; ...de matériaux et couleurs - 2 = Ivoire clair
__RECOGNIZE__ - TPLG: 366; TPLG_OD: 9000; GENERATE: 1
CTLG_EXTERNAL_LINK - 0, DocType: 2; 0, Tag: 0; 0, Crc: 1977773087; 1, DocType: 2; 1, Tag: 100; 1, Crc: 1977773087; 2, DocType: 2; 2, Tag: 200; 2, Crc: 1977773087; 3, DocType: 9; 3, Tag: 0; 3, Crc: -1765334021
IFC_PSET_PolygonOffset - polygonOffsetFactor: 2; polygonOffsetUnits: 2
IFC_Pset_Alignment - Alignment: 0
IFC_Pset_Strat_Detail_Align - ExternalFace: 0
IFC_Pset_Caractéristiques - Stratigraphie: default [165,00]; Épaisseur: 16.5 cm; Épaisseur VARIABLE: no
IFC_Pset_Caractéristiques_FRUIT - Fruit: no; Taille: 0 cm
IFC_Pset_Géométrie - Forme en Élévation: rectangle
IFC_Pset_Système de Référence Altimétrique_SUPÉRIEUR - sous Niveau: <aucun>
IFC_Pset_Matériaux - Face gauche: Ivoire clair; Face droite: Ivoire clair; Face latérale: Ivoire clair
Pset_WallCommon - Reference: default [165,00] (..\VERTICALES\Default\)
BaseQuantities - NominalWidth: 16.5 cm
Name | In | __RECOGNIZE__, ID = IFC_Pset_Caractéristiques, ID | Numérotation | Numéro niveau | Titre niveau | Longueur (cm) = NominalLength (cm) | IFC_Pset_Géométrie, Hauteur (cm) = IFC_Pset_Géométrie_P1 (POINT initial), Hauteur (cm) = IFC_Pset_Géométrie_P2 (POINT final), Hauteur (cm) = Hauteur Maximale (cm) = Hauteur Minimale (cm) = NominalHeight (cm) | IFC_Pset_Géométrie, Cote (cm) = IFC_Pset_Géométrie_P1 (POINT initial), Cote (cm) = IFC_Pset_Géométrie_P2 (POINT final), Cote (cm) = IFC_Pset_Système de Référence Altimétrique_INFÉRIEUR, delta (cm) = IFC_Pset_Système de Référence Altimétrique_INFÉRIEUR, delta (P1) (cm) = IFC_Pset_Système de Référence Altimétrique_INFÉRIEUR, delta (P2) (cm) | IFC_Pset_Géométrie_P1 (POINT initial), Angle XY (deg) | IFC_Pset_Géométrie_P2 (POINT final), Angle XY (deg) | IFC_Pset_Système de Référence Altimétrique_SUPÉRIEUR, NIVEAU | IFC_Pset_Système de Référence Altimétrique_SUPÉRIEUR, delta (cm) = IFC_Pset_Système de Référence Altimétrique_SUPÉRIEUR, delta (P1) (cm) = IFC_Pset_Système de Référence Altimétrique_SUPÉRIEUR, delta (P2) (cm) | IFC_Pset_Système de Référence Altimétrique_INFÉRIEUR, NIVEAU | sous Niveau | Longueur Pied (cm) = Longueur Tête (cm) | Surface en Plan (cm2) = Surface Pied (cm2) = Surface Tête (cm2) | Surface de la Paroi (cm2) | Volume (cm3) | GrossVolume (cm3) | NetVolume (cm3) | GrossFootprintArea (cm2) = NetFootprintArea (cm2) | GrossSideArea (cm2) | NetSideArea (cm2)
Enveloppe 135031 | Rez-de-Jardin | 135031 | 0313 | 02 | Rez-de-Jardin | 404.238 | 206.4 | 0 | 57.7018 | 237.702 | HAUT Rez-de-Jardin (Rez-de-chaussée 1047) | -135 | Rez-de-Jardin (Rez-de-Jardin 15545) | extérieur | 404.2 | 6900 | 83400 | 1420000 | 1376676 | 1198071 | 6669.93 | 83434.9 | 72610.4
Enveloppe 152282 | Niveau 2 | 152282 | 0353 | 05 | Niveau 2 | 90.9021 | 235 | 1.42109e-12 | 90.174 | 270.174 | HAUT Niveau 2 (Mezzanine 49003) | 0 | Niveau 2 (Niveau 2 13545) | <aucun> | 90.9 | 1500 | 21400 | 360000 | 352473 | 352473 | 1499.88 | 21362 | 21362

# IfcWallStandardCase: default 166.562530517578, Enveloppe 150651
In: Niveau 2
Type - Material: <aucun> 16.6563 cm
Description: Enveloppe; Group: ...de stratigraphies = default; ...de matériaux et couleurs = Ivoire clair; ...de matériaux et couleurs - 1 = Ivoire clair; ...de matériaux et couleurs - 2 = Ivoire clair
__RECOGNIZE__ - ID: 150651; TPLG: 366; TPLG_OD: 9000; GENERATE: 1
CTLG_EXTERNAL_LINK - 0, DocType: 2; 0, Tag: 0; 0, Crc: 1977773087; 1, DocType: 2; 1, Tag: 100; 1, Crc: 1977773087; 2, DocType: 2; 2, Tag: 200; 2, Crc: 1977773087; 3, DocType: 9; 3, Tag: 0; 3, Crc: -270187002
IFC_PSET_PolygonOffset - polygonOffsetFactor: 2; polygonOffsetUnits: 2
IFC_Pset_Alignment - Alignment: 1
IFC_Pset_Strat_Detail_Align - ExternalFace: 0
IFC_Pset_Caractéristiques - ID: 150651; Numérotation: 0334; Numéro niveau: 05; Titre niveau: Niveau 2; Stratigraphie: default [166,56]; Épaisseur: 16.66 cm; Épaisseur VARIABLE: no
IFC_Pset_Caractéristiques_FRUIT - Fruit: no; Taille: 0 cm
IFC_Pset_Géométrie - Forme en Élévation: rectangle; Longueur: 148.484 cm; Hauteur: 209 cm; Cote: 1.42109e-12 cm
IFC_Pset_Géométrie_P1 (POINT initial) - Hauteur: 209 cm; Cote: 1.42109e-12 cm; Angle XY: 90.3395 deg
IFC_Pset_Géométrie_P2 (POINT final) - Hauteur: 209 cm; Cote: 1.42109e-12 cm; Angle XY: 270.339 deg
IFC_Pset_Système de Référence Altimétrique_SUPÉRIEUR - NIVEAU: HAUT Niveau 2 (Mezzanine 49003); delta: -26 cm; delta (P1): -26 cm; delta (P2): -26 cm; sous Niveau: <aucun>
IFC_Pset_Système de Référence Altimétrique_INFÉRIEUR - NIVEAU: Niveau 2 (Niveau 2 13545); delta: 1.42109e-12 cm; delta (P1): 1.42109e-12 cm; delta (P2): 1.42109e-12 cm; sous Niveau: <aucun>
IFC_Pset_Données Métré - Longueur Pied: 148.5 cm; Longueur Tête: 148.5 cm; Hauteur Maximale: 209 cm; Hauteur Minimale: 209 cm; Surface en Plan: 2500 cm2; Surface Pied: 2500 cm2; Surface Tête: 2500 cm2; Surface de la Paroi: 31000 cm2; Volume: 530000 cm3
IFC_Pset_Matériaux - Face gauche: Ivoire clair; Face droite: Ivoire clair; Face latérale: Ivoire clair
Pset_WallCommon - Reference: default [166,56] (..\VERTICALES\Default\)
BaseQuantities - GrossVolume: 516895 cm3; NetVolume: 516895 cm3; NominalLength: 148.484 cm; NominalWidth: 16.6563 cm; NominalHeight: 209 cm; GrossFootprintArea: 2473.18 cm2; NetFootprintArea: 2473.18 cm2; GrossSideArea: 31033.1 cm2; NetSideArea: 31033.1 cm2

# IfcWallStandardCase: default 170, Enveloppe 54093
In: Rez-de-Jardin
Type - Material: <aucun> 17 cm
Description: Enveloppe; Group: ...de stratigraphies = default; ...de matériaux et couleurs = Ivoire clair; ...de matériaux et couleurs - 1 = Ivoire clair; ...de matériaux et couleurs - 2 = Ivoire clair
__RECOGNIZE__ - ID: 54093; TPLG: 366; TPLG_OD: 9000; GENERATE: 1
CTLG_EXTERNAL_LINK - 0, DocType: 2; 0, Tag: 0; 0, Crc: 1977773087; 1, DocType: 2; 1, Tag: 100; 1, Crc: 1977773087; 2, DocType: 2; 2, Tag: 200; 2, Crc: 1977773087; 3, DocType: 9; 3, Tag: 0; 3, Crc: -2124883226
IFC_PSET_PolygonOffset - polygonOffsetFactor: 2; polygonOffsetUnits: 2
IFC_Pset_Alignment - Alignment: 1
IFC_Pset_Strat_Detail_Align - ExternalFace: 1
IFC_Pset_Caractéristiques - ID: 54093; Numérotation: 0092; Numéro niveau: 02; Titre niveau: Rez-de-Jardin; Stratigraphie: default [170,00]; Épaisseur: 17 cm; Épaisseur VARIABLE: no
IFC_Pset_Caractéristiques_FRUIT - Fruit: no; Taille: 0 cm
IFC_Pset_Géométrie - Forme en Élévation: rectangle; Longueur: 137.005 cm; Hauteur: 291.413 cm; Cote: -1.94511e-11 cm
IFC_Pset_Géométrie_P1 (POINT initial) - Hauteur: 291.413 cm; Cote: -1.94511e-11 cm; Angle XY: 179.572 deg
IFC_Pset_Géométrie_P2 (POINT final) - Hauteur: 291.413 cm; Cote: -1.94511e-11 cm; Angle XY: 359.572 deg
IFC_Pset_Système de Référence Altimétrique_SUPÉRIEUR - NIVEAU: HAUT Rez-de-Jardin (Rez-de-chaussée 1047); delta: 0.0128504 cm; delta (P1): 0.0128504 cm; delta (P2): 0.0128504 cm; sous Niveau: <aucun>
IFC_Pset_Système de Référence Altimétrique_INFÉRIEUR - NIVEAU: Rez-de-Jardin (Rez-de-Jardin 15545); delta: -1.94511e-11 cm; delta (P1): -1.94511e-11 cm; delta (P2): -1.94511e-11 cm; sous Niveau: <aucun>
IFC_Pset_Données Métré - Longueur Pied: 137 cm; Longueur Tête: 137 cm; Hauteur Maximale: 291.4 cm; Hauteur Minimale: 291.4 cm; Surface en Plan: 2300 cm2; Surface Pied: 2300 cm2; Surface Tête: 2300 cm2; Surface de la Paroi: 39900 cm2; Volume: 680000 cm3
IFC_Pset_Matériaux - Face gauche: Ivoire clair; Face droite: Ivoire clair; Face latérale: Ivoire clair
Pset_WallCommon - Reference: default [170,00] (..\VERTICALES\Default\)
BaseQuantities - GrossVolume: 678725 cm3; NetVolume: 359685 cm3; NominalLength: 137.005 cm; NominalWidth: 17 cm; NominalHeight: 291.413 cm; GrossFootprintArea: 2329.08 cm2; NetFootprintArea: 2329.08 cm2; GrossSideArea: 39925 cm2; NetSideArea: 21158 cm2

# IfcWallStandardCase: default 175 (2)
Type - Material: <aucun> 17.5 cm
Description: Enveloppe; Group: ...de stratigraphies = default; ...de matériaux et couleurs = Ivoire clair; ...de matériaux et couleurs - 1 = Ivoire clair; ...de matériaux et couleurs - 2 = Ivoire clair
__RECOGNIZE__ - TPLG: 366; TPLG_OD: 9000; GENERATE: 1
CTLG_EXTERNAL_LINK - 0, DocType: 2; 0, Tag: 0; 0, Crc: 1977773087; 1, DocType: 2; 1, Tag: 100; 1, Crc: 1977773087; 2, DocType: 2; 2, Tag: 200; 2, Crc: 1977773087; 3, DocType: 9; 3, Tag: 0; 3, Crc: -927974492
IFC_PSET_PolygonOffset - polygonOffsetFactor: 2; polygonOffsetUnits: 2
IFC_Pset_Caractéristiques - Stratigraphie: default [175,00]; Épaisseur: 17.5 cm; Épaisseur VARIABLE: no
IFC_Pset_Caractéristiques_FRUIT - Fruit: no; Taille: 0 cm
IFC_Pset_Géométrie - Forme en Élévation: rectangle
IFC_Pset_Système de Référence Altimétrique_SUPÉRIEUR - sous Niveau: <aucun>
IFC_Pset_Système de Référence Altimétrique_INFÉRIEUR - sous Niveau: <aucun>
IFC_Pset_Matériaux - Face gauche: Ivoire clair; Face droite: Ivoire clair; Face latérale: Ivoire clair
Pset_WallCommon - Reference: default [175,00] (..\VERTICALES\Default\)
BaseQuantities - NominalWidth: 17.5 cm
Name | In | __RECOGNIZE__, ID = IFC_Pset_Caractéristiques, ID | Alignment = ExternalFace | Numérotation | Numéro niveau | Titre niveau | Longueur (cm) = NominalLength (cm) | IFC_Pset_Géométrie, Hauteur (cm) = IFC_Pset_Géométrie_P1 (POINT initial), Hauteur (cm) = IFC_Pset_Géométrie_P2 (POINT final), Hauteur (cm) = NominalHeight (cm) | IFC_Pset_Géométrie, Cote (cm) = IFC_Pset_Géométrie_P1 (POINT initial), Cote (cm) = IFC_Pset_Géométrie_P2 (POINT final), Cote (cm) = IFC_Pset_Système de Référence Altimétrique_INFÉRIEUR, delta (cm) = IFC_Pset_Système de Référence Altimétrique_INFÉRIEUR, delta (P1) (cm) = IFC_Pset_Système de Référence Altimétrique_INFÉRIEUR, delta (P2) (cm) | IFC_Pset_Géométrie_P1 (POINT initial), Angle XY (deg) | IFC_Pset_Géométrie_P2 (POINT final), Angle XY (deg) | IFC_Pset_Système de Référence Altimétrique_SUPÉRIEUR, NIVEAU | IFC_Pset_Système de Référence Altimétrique_SUPÉRIEUR, delta (cm) = IFC_Pset_Système de Référence Altimétrique_SUPÉRIEUR, delta (P1) (cm) = IFC_Pset_Système de Référence Altimétrique_SUPÉRIEUR, delta (P2) (cm) | IFC_Pset_Système de Référence Altimétrique_INFÉRIEUR, NIVEAU | Longueur Pied (cm) = Longueur Tête (cm) | Hauteur Maximale (cm) = Hauteur Minimale (cm) | Surface en Plan (cm2) = Surface Pied (cm2) = Surface Tête (cm2) | Surface de la Paroi (cm2) | Volume (cm3) | GrossVolume (cm3) = NetVolume (cm3) | GrossFootprintArea (cm2) = NetFootprintArea (cm2) | GrossSideArea (cm2) = NetSideArea (cm2)
Enveloppe 54122 | Rez-de-Jardin | 54122 | 1 | 0093 | 02 | Rez-de-Jardin | 169.575 | 291.413 | -1.94511e-11 | 90.2375 | 270.237 | HAUT Rez-de-Jardin (Rez-de-chaussée 1047) | 0.0128504 | Rez-de-Jardin (Rez-de-Jardin 15545) | 169.6 | 291.4 | 3100 | 49400 | 890000 | 864786 | 2967.56 | 49416.4
Enveloppe 119881 | Niveau 1 | 119881 | 0 | 0288 | 04 | Niveau 1 | 135.464 | 376.102 | 0.0128504 | 90.174 | 270.174 | HAUT Niveau 1 (Niveau 2 13545) | 0 | Niveau 1 (Niveau 1 2343) | 135.5 | 376.1 | 2400 | 51000 | 920000 | 891592 | 2370.61 | 50948.1

# IfcWallStandardCase: default 180 (6)
Type - Material: <aucun> 18 cm
Description: Enveloppe; Group: ...de stratigraphies = default; ...de matériaux et couleurs = Ivoire clair; ...de matériaux et couleurs - 1 = Ivoire clair; ...de matériaux et couleurs - 2 = Ivoire clair
__RECOGNIZE__ - TPLG: 366; TPLG_OD: 9000; GENERATE: 1
CTLG_EXTERNAL_LINK - 0, DocType: 2; 0, Tag: 0; 0, Crc: 1977773087; 1, DocType: 2; 1, Tag: 100; 1, Crc: 1977773087; 2, DocType: 2; 2, Tag: 200; 2, Crc: 1977773087; 3, DocType: 9; 3, Tag: 0; 3, Crc: -573407016
IFC_PSET_PolygonOffset - polygonOffsetFactor: 2; polygonOffsetUnits: 2
IFC_Pset_Caractéristiques - Stratigraphie: default [180,00]; Épaisseur: 18 cm; Épaisseur VARIABLE: no
IFC_Pset_Caractéristiques_FRUIT - Fruit: no; Taille: 0 cm
IFC_Pset_Système de Référence Altimétrique_SUPÉRIEUR - sous Niveau: <aucun>
IFC_Pset_Système de Référence Altimétrique_INFÉRIEUR - sous Niveau: <aucun>
IFC_Pset_Matériaux - Face gauche: Ivoire clair; Face droite: Ivoire clair; Face latérale: Ivoire clair
Pset_WallCommon - Reference: default [180,00] (..\VERTICALES\Default\)
BaseQuantities - NominalWidth: 18 cm
Name | In | __RECOGNIZE__, ID = IFC_Pset_Caractéristiques, ID | Alignment | ExternalFace | Numérotation | Numéro niveau | Titre niveau | Forme en Élévation | Longueur (cm) = NominalLength (cm) | IFC_Pset_Géométrie, Hauteur (cm) = IFC_Pset_Géométrie_P1 (POINT initial), Hauteur (cm) | IFC_Pset_Géométrie, Cote (cm) = IFC_Pset_Géométrie_P1 (POINT initial), Cote (cm) = IFC_Pset_Géométrie_P2 (POINT final), Cote (cm) = IFC_Pset_Système de Référence Altimétrique_INFÉRIEUR, delta (cm) = IFC_Pset_Système de Référence Altimétrique_INFÉRIEUR, delta (P1) (cm) = IFC_Pset_Système de Référence Altimétrique_INFÉRIEUR, delta (P2) (cm) | IFC_Pset_Géométrie_P1 (POINT initial), Angle XY (deg) | IFC_Pset_Géométrie_P2 (POINT final), Hauteur (cm) | IFC_Pset_Géométrie_P2 (POINT final), Angle XY (deg) | IFC_Pset_Système de Référence Altimétrique_SUPÉRIEUR, NIVEAU | IFC_Pset_Système de Référence Altimétrique_SUPÉRIEUR, delta (cm) = IFC_Pset_Système de Référence Altimétrique_SUPÉRIEUR, delta (P1) (cm) = IFC_Pset_Système de Référence Altimétrique_SUPÉRIEUR, delta (P2) (cm) | IFC_Pset_Système de Référence Altimétrique_INFÉRIEUR, NIVEAU | Longueur Pied (cm) | Longueur Tête (cm) | Hauteur Maximale (cm) | Hauteur Minimale (cm) | Surface en Plan (cm2) = Surface Pied (cm2) | Surface Tête (cm2) | Surface de la Paroi (cm2) | Volume (cm3) | GrossVolume (cm3) | NetVolume (cm3) | NominalHeight (cm) | GrossFootprintArea (cm2) = NetFootprintArea (cm2) | GrossSideArea (cm2) | NetSideArea (cm2)
Enveloppe 230211 | Rez-de-Jardin | 230211 | 0 | 1 | 0521 | 02 | Rez-de-Jardin | rectangle | 23.6994 | 291.413 | -1.94511e-11 | 1.52743 | 291.413 | 181.527 | HAUT Rez-de-Jardin (Rez-de-chaussée 1047) | 0.0128504 | Rez-de-Jardin (Rez-de-Jardin 15545) | 23.7 | 23.7 | 291.4 | 291.4 | 400 | 400 | 6900 | 120000 | 124314 | 124314 | 291.413 | 426.59 | 6906.33 | 6906.33
Enveloppe 311187 | Rez-de-Jardin | 311187 | 1 | 1 | 0547 | 02 | Rez-de-Jardin | trapèze | 89.3747 | 191.4 | -1.94511e-11 | 179.525 | 145.112 | 359.525 | HAUT Rez-de-Jardin (Rez-de-chaussée 1047) | 0 | Rez-de-Jardin (Rez-de-Jardin 15545) | 89.4 | 100.7 | 191.4 | 145.1 | 1600 | 1900 | 15800 | 280000 | 284014 | 284014 | 176.544 | 1608.74 | 15778.5 | 15778.5
Enveloppe 320194 | Rez-de-Jardin | 320194 | 1 | 1 | 0554 | 02 | Rez-de-Jardin | trapèze | 88.6603 | 191.4 | -1.94511e-11 | 179.525 | 145.112 | 359.525 | HAUT Rez-de-Jardin (Rez-de-chaussée 1047) | 0 | Rez-de-Jardin (Rez-de-Jardin 15545) | 88.7 | 100.1 | 191.4 | 145.1 | 1600 | 1900 | 15700 | 280000 | 281691 | 281691 | 176.511 | 1595.88 | 15649.5 | 15649.5
Enveloppe 377929 | Rez-de-chaussée | 377929 | 1 | 0 | 0661 | 03 | Rez-de-chaussée | rectangle | 21.6125 | 477.795 | 0.0128504 | 92.0332 | 477.795 | 272.033 | HAUT Rez-de-chaussée (Niveau 1 2343) | 0.0128504 | Rez-de-chaussée (Rez-de-chaussée 1047) | 21.6 | 21.6 | 477.8 | 477.8 | 400 | 400 | 10300 | 190000 | 185874 | 185874 | 477.795 | 389.024 | 10326.3 | 10326.3
Enveloppe 378348 | Rez-de-chaussée | 378348 | 1 | 0 | 0663 | 03 | Rez-de-chaussée | rectangle | 167.094 | 477.795 | 0.0128504 | 89.6376 | 477.795 | 269.638 | HAUT Rez-de-chaussée (Niveau 1 2343) | 0.0128504 | Rez-de-chaussée (Rez-de-chaussée 1047) | 167.1 | 167.1 | 477.8 | 477.8 | 3000 | 3000 | 79800 | 1440000 | 1437058 | 816786 | 477.795 | 3007.69 | 79836.6 | 45377
Enveloppe 158794 | Niveau 2 | 158794 | 1 | 0 | 0365 | 05 | Niveau 2 | rectangle | 316.704 | 234.008 | 1.42109e-12 | 90.6226 | 234.008 | 270.623 | HAUT Niveau 2 (Mezzanine 49003) | -0.992436 | Niveau 2 (Niveau 2 13545) | 316.7 | 316.7 | 234 | 234 | 5700 | 5700 | 74100 | 1330000 | 1334001 | 1334001 | 234.008 | 5700.67 | 74111.2 | 74111.2

# IfcWallStandardCase: default 190, Enveloppe 67258
In: Rez-de-Jardin
Type - Material: <aucun> 19 cm
Description: Enveloppe; Group: ...de stratigraphies = default; ...de matériaux et couleurs = Ivoire clair; ...de matériaux et couleurs - 1 = Ivoire clair; ...de matériaux et couleurs - 2 = Ivoire clair
__RECOGNIZE__ - ID: 67258; TPLG: 366; TPLG_OD: 9000; GENERATE: 1
CTLG_EXTERNAL_LINK - 0, DocType: 2; 0, Tag: 0; 0, Crc: 1977773087; 1, DocType: 2; 1, Tag: 100; 1, Crc: 1977773087; 2, DocType: 2; 2, Tag: 200; 2, Crc: 1977773087; 3, DocType: 9; 3, Tag: 0; 3, Crc: -1215823443
IFC_PSET_PolygonOffset - polygonOffsetFactor: 2; polygonOffsetUnits: 2
IFC_Pset_Alignment - Alignment: 0
IFC_Pset_Strat_Detail_Align - ExternalFace: 1
IFC_Pset_Caractéristiques - ID: 67258; Numérotation: 0124; Numéro niveau: 02; Titre niveau: Rez-de-Jardin; Stratigraphie: default [190,00]; Épaisseur: 19 cm; Épaisseur VARIABLE: no
IFC_Pset_Caractéristiques_FRUIT - Fruit: no; Taille: 0 cm
IFC_Pset_Géométrie - Forme en Élévation: rectangle; Longueur: 158.316 cm; Hauteur: 291.413 cm; Cote: -1.94511e-11 cm
IFC_Pset_Géométrie_P1 (POINT initial) - Hauteur: 291.413 cm; Cote: -1.94511e-11 cm; Angle XY: 0.192193 deg
IFC_Pset_Géométrie_P2 (POINT final) - Hauteur: 291.413 cm; Cote: -1.94511e-11 cm; Angle XY: 180.192 deg
IFC_Pset_Système de Référence Altimétrique_SUPÉRIEUR - NIVEAU: HAUT Rez-de-Jardin (Rez-de-chaussée 1047); delta: 0.0128504 cm; delta (P1): 0.0128504 cm; delta (P2): 0.0128504 cm; sous Niveau: <aucun>
IFC_Pset_Système de Référence Altimétrique_INFÉRIEUR - NIVEAU: Rez-de-Jardin (Rez-de-Jardin 15545); delta: -1.94511e-11 cm; delta (P1): -1.94511e-11 cm; delta (P2): -1.94511e-11 cm; sous Niveau: <aucun>
IFC_Pset_Données Métré - Longueur Pied: 158.3 cm; Longueur Tête: 158.3 cm; Hauteur Maximale: 291.4 cm; Hauteur Minimale: 291.4 cm; Surface en Plan: 3000 cm2; Surface Pied: 3000 cm2; Surface Tête: 3000 cm2; Surface de la Paroi: 46100 cm2; Volume: 880000 cm3
IFC_Pset_Matériaux - Face gauche: Ivoire clair; Face droite: Ivoire clair; Face latérale: Ivoire clair
Pset_WallCommon - Reference: default [190,00] (..\VERTICALES\Default\)
BaseQuantities - GrossVolume: 876572 cm3; NetVolume: 876572 cm3; NominalLength: 158.316 cm; NominalWidth: 19 cm; NominalHeight: 291.413 cm; GrossFootprintArea: 3008 cm2; NetFootprintArea: 3008 cm2; GrossSideArea: 46135.4 cm2; NetSideArea: 46135.4 cm2

# IfcWallStandardCase: default 195.656921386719, Enveloppe 7411
In: Rez-de-chaussée
Type - Material: <aucun> 19.5657 cm
Description: Enveloppe; Group: ...de stratigraphies = default; ...de matériaux et couleurs = Ivoire clair; ...de matériaux et couleurs - 1 = Ivoire clair; ...de matériaux et couleurs - 2 = Ivoire clair
__RECOGNIZE__ - ID: 7411; TPLG: 366; TPLG_OD: 9000; GENERATE: 1
CTLG_EXTERNAL_LINK - 0, DocType: 2; 0, Tag: 0; 0, Crc: 1977773087; 1, DocType: 2; 1, Tag: 100; 1, Crc: 1977773087; 2, DocType: 2; 2, Tag: 200; 2, Crc: 1977773087; 3, DocType: 9; 3, Tag: 0; 3, Crc: 585017794
IFC_PSET_PolygonOffset - polygonOffsetFactor: 2; polygonOffsetUnits: 2
IFC_Pset_Alignment - Alignment: 0
IFC_Pset_Strat_Detail_Align - ExternalFace: 0
IFC_Pset_Caractéristiques - ID: 7411; Numérotation: 0044; Numéro niveau: 03; Titre niveau: Rez-de-chaussée; Stratigraphie: default [195,66]; Épaisseur: 19.57 cm; Épaisseur VARIABLE: no
IFC_Pset_Caractéristiques_FRUIT - Fruit: no; Taille: 0 cm
IFC_Pset_Géométrie - Forme en Élévation: rectangle; Longueur: 201.369 cm; Hauteur: 397.095 cm; Cote: 0.0128504 cm
IFC_Pset_Géométrie_P1 (POINT initial) - Hauteur: 397.095 cm; Cote: 0.0128504 cm; Angle XY: 135.913 deg
IFC_Pset_Géométrie_P2 (POINT final) - Hauteur: 397.095 cm; Cote: 0.0128504 cm; Angle XY: 315.913 deg
IFC_Pset_Système de Référence Altimétrique_SUPÉRIEUR - NIVEAU: HAUT Rez-de-chaussée (Niveau 1 2343); delta: -80.6871 cm; delta (P1): -80.6871 cm; delta (P2): -80.6871 cm; sous Niveau: <aucun>
IFC_Pset_Système de Référence Altimétrique_INFÉRIEUR - NIVEAU: Rez-de-chaussée (Rez-de-chaussée 1047); delta: 0.0128504 cm; delta (P1): 0.0128504 cm; delta (P2): 0.0128504 cm; sous Niveau: <aucun>
IFC_Pset_Données Métré - Longueur Pied: 201.4 cm; Longueur Tête: 201.4 cm; Hauteur Maximale: 397.1 cm; Hauteur Minimale: 397.1 cm; Surface en Plan: 4100 cm2; Surface Pied: 4100 cm2; Surface Tête: 4100 cm2; Surface de la Paroi: 80000 cm2; Volume: 1600000 cm3
IFC_Pset_Matériaux - Face gauche: Ivoire clair; Face droite: Ivoire clair; Face latérale: Ivoire clair
Pset_WallCommon - Reference: default [195,66] (..\VERTICALES\Default\)
BaseQuantities - GrossVolume: 1564526 cm3; NetVolume: 1241983 cm3; NominalLength: 201.369 cm; NominalWidth: 19.5657 cm; NominalHeight: 397.095 cm; GrossFootprintArea: 3939.93 cm2; NetFootprintArea: 3939.93 cm2; GrossSideArea: 79962.7 cm2; NetSideArea: 63477.6 cm2

# IfcWallStandardCase: default 20, Enveloppe 104172
In: Niveau 1
Type - Material: <aucun> 2 cm
Description: Enveloppe; Group: ...de stratigraphies = default; ...de matériaux et couleurs = Ivoire clair; ...de matériaux et couleurs - 1 = Ivoire clair; ...de matériaux et couleurs - 2 = Ivoire clair
__RECOGNIZE__ - ID: 104172; TPLG: 366; TPLG_OD: 9000; GENERATE: 1
CTLG_EXTERNAL_LINK - 0, DocType: 2; 0, Tag: 0; 0, Crc: 1977773087; 1, DocType: 2; 1, Tag: 100; 1, Crc: 1977773087; 2, DocType: 2; 2, Tag: 200; 2, Crc: 1977773087; 3, DocType: 9; 3, Tag: 0; 3, Crc: 1431571417
IFC_PSET_PolygonOffset - polygonOffsetFactor: 2; polygonOffsetUnits: 2
IFC_Pset_Alignment - Alignment: 0
IFC_Pset_Strat_Detail_Align - ExternalFace: 0
IFC_Pset_Caractéristiques - ID: 104172; Numérotation: 0263; Numéro niveau: 04; Titre niveau: Niveau 1; Stratigraphie: default [20,00]; Épaisseur: 2 cm; Épaisseur VARIABLE: no
IFC_Pset_Caractéristiques_FRUIT - Fruit: no; Taille: 0 cm
IFC_Pset_Géométrie - Forme en Élévation: rectangle; Longueur: 58.0065 cm; Hauteur: 298.702 cm; Cote: 0.0128504 cm
IFC_Pset_Géométrie_P1 (POINT initial) - Hauteur: 298.702 cm; Cote: 0.0128504 cm; Angle XY: 89.9764 deg
IFC_Pset_Géométrie_P2 (POINT final) - Hauteur: 298.702 cm; Cote: 0.0128504 cm; Angle XY: 269.976 deg
IFC_Pset_Système de Référence Altimétrique_SUPÉRIEUR - NIVEAU: HAUT Niveau 1 (Niveau 2 13545); delta: -77.4 cm; delta (P1): -77.4 cm; delta (P2): -77.4 cm; sous Niveau: <aucun>
IFC_Pset_Système de Référence Altimétrique_INFÉRIEUR - NIVEAU: Niveau 1 (Niveau 1 2343); delta: 0.0128504 cm; delta (P1): 0.0128504 cm; delta (P2): 0.0128504 cm; sous Niveau: <aucun>
IFC_Pset_Données Métré - Longueur Pied: 58 cm; Longueur Tête: 58 cm; Hauteur Maximale: 298.7 cm; Hauteur Minimale: 298.7 cm; Surface en Plan: 100 cm2; Surface Pied: 100 cm2; Surface Tête: 100 cm2; Surface de la Paroi: 17300 cm2; Volume: 30000 cm3
IFC_Pset_Matériaux - Face gauche: Ivoire clair; Face droite: Ivoire clair; Face latérale: Ivoire clair
Pset_WallCommon - Reference: default [20,00] (..\VERTICALES\Default\)
BaseQuantities - GrossVolume: 34653.3 cm3; NetVolume: 34653.3 cm3; NominalLength: 58.0065 cm; NominalWidth: 2 cm; NominalHeight: 298.702 cm; GrossFootprintArea: 116.013 cm2; NetFootprintArea: 116.013 cm2; GrossSideArea: 17326.7 cm2; NetSideArea: 17326.7 cm2

# IfcWallStandardCase: default 200 (3)
Type - Material: <aucun> 20 cm
Description: Enveloppe; Group: ...de stratigraphies = default; ...de matériaux et couleurs = Ivoire clair; ...de matériaux et couleurs - 1 = Ivoire clair; ...de matériaux et couleurs - 2 = Ivoire clair
__RECOGNIZE__ - TPLG: 366; TPLG_OD: 9000; GENERATE: 1
CTLG_EXTERNAL_LINK - 0, DocType: 2; 0, Tag: 0; 0, Crc: 1977773087; 1, DocType: 2; 1, Tag: 100; 1, Crc: 1977773087; 2, DocType: 2; 2, Tag: 200; 2, Crc: 1977773087; 3, DocType: 9; 3, Tag: 0; 3, Crc: -1269062341
IFC_PSET_PolygonOffset - polygonOffsetFactor: 2; polygonOffsetUnits: 2
IFC_Pset_Alignment - Alignment: 1
IFC_Pset_Strat_Detail_Align - ExternalFace: 0
IFC_Pset_Caractéristiques - Stratigraphie: default [200,00]; Épaisseur: 20 cm; Épaisseur VARIABLE: no
IFC_Pset_Caractéristiques_FRUIT - Fruit: no; Taille: 0 cm
IFC_Pset_Géométrie - Forme en Élévation: rectangle
IFC_Pset_Système de Référence Altimétrique_SUPÉRIEUR - sous Niveau: <aucun>
IFC_Pset_Système de Référence Altimétrique_INFÉRIEUR - sous Niveau: <aucun>
IFC_Pset_Matériaux - Face gauche: Ivoire clair; Face droite: Ivoire clair; Face latérale: Ivoire clair
Pset_WallCommon - Reference: default [200,00] (..\VERTICALES\Default\)
BaseQuantities - NominalWidth: 20 cm
Name | In | __RECOGNIZE__, ID = IFC_Pset_Caractéristiques, ID | Numérotation | Numéro niveau | Titre niveau | Longueur (cm) = NominalLength (cm) | IFC_Pset_Géométrie, Hauteur (cm) = IFC_Pset_Géométrie_P1 (POINT initial), Hauteur (cm) = IFC_Pset_Géométrie_P2 (POINT final), Hauteur (cm) = NominalHeight (cm) | IFC_Pset_Géométrie, Cote (cm) = IFC_Pset_Géométrie_P1 (POINT initial), Cote (cm) = IFC_Pset_Géométrie_P2 (POINT final), Cote (cm) = IFC_Pset_Système de Référence Altimétrique_INFÉRIEUR, delta (cm) = IFC_Pset_Système de Référence Altimétrique_INFÉRIEUR, delta (P1) (cm) = IFC_Pset_Système de Référence Altimétrique_INFÉRIEUR, delta (P2) (cm) | IFC_Pset_Géométrie_P1 (POINT initial), Angle XY (deg) | IFC_Pset_Géométrie_P2 (POINT final), Angle XY (deg) | IFC_Pset_Système de Référence Altimétrique_SUPÉRIEUR, NIVEAU | IFC_Pset_Système de Référence Altimétrique_SUPÉRIEUR, delta (cm) = IFC_Pset_Système de Référence Altimétrique_SUPÉRIEUR, delta (P1) (cm) = IFC_Pset_Système de Référence Altimétrique_SUPÉRIEUR, delta (P2) (cm) | IFC_Pset_Système de Référence Altimétrique_INFÉRIEUR, NIVEAU | Longueur Pied (cm) = Longueur Tête (cm) | Hauteur Maximale (cm) = Hauteur Minimale (cm) | Surface en Plan (cm2) = Surface Pied (cm2) = Surface Tête (cm2) | Surface de la Paroi (cm2) | Volume (cm3) | GrossVolume (cm3) = NetVolume (cm3) | GrossFootprintArea (cm2) = NetFootprintArea (cm2) | GrossSideArea (cm2) = NetSideArea (cm2)
Enveloppe 92396 | Rez-de-Jardin | 92396 | 0181 | 02 | Rez-de-Jardin | 93.2378 | 161.4 | -1.94511e-11 | 44.3864 | 224.386 | HAUT Rez-de-Jardin (Rez-de-chaussée 1047) | -130 | Rez-de-Jardin (Rez-de-Jardin 15545) | 93.2 | 161.4 | 1900 | 15000 | 300000 | 300972 | 1864.76 | 15048.6
Enveloppe 92405 | Rez-de-Jardin | 92405 | 0182 | 02 | Rez-de-Jardin | 233.518 | 161.4 | -1.94511e-11 | 90.5725 | 270.572 | HAUT Rez-de-Jardin (Rez-de-chaussée 1047) | -130 | Rez-de-Jardin (Rez-de-Jardin 15545) | 233.5 | 161.4 | 4700 | 37700 | 750000 | 753799 | 4670.37 | 37689.9
Enveloppe 128736 | Niveau 1 | 128736 | 0300 | 04 | Niveau 1 | 46.6074 | 376.102 | 0.0128504 | 90.1529 | 270.153 | HAUT Niveau 1 (Niveau 2 13545) | 0 | Niveau 1 (Niveau 1 2343) | 46.6 | 376.1 | 900 | 17500 | 350000 | 350583 | 932.147 | 17529.1

# IfcWallStandardCase: default 205, Enveloppe 367501
In: Rez-de-chaussée
Type - Material: <aucun> 20.5 cm
Description: Enveloppe; Group: ...de stratigraphies = default; ...de matériaux et couleurs = Ivoire clair; ...de matériaux et couleurs - 1 = Ivoire clair; ...de matériaux et couleurs - 2 = Ivoire clair
__RECOGNIZE__ - ID: 367501; TPLG: 366; TPLG_OD: 9000; GENERATE: 1
CTLG_EXTERNAL_LINK - 0, DocType: 2; 0, Tag: 0; 0, Crc: 1977773087; 1, DocType: 2; 1, Tag: 100; 1, Crc: 1977773087; 2, DocType: 2; 2, Tag: 200; 2, Crc: 1977773087; 3, DocType: 9; 3, Tag: 0; 3, Crc: 1983667753
IFC_PSET_PolygonOffset - polygonOffsetFactor: 2; polygonOffsetUnits: 2
IFC_Pset_Alignment - Alignment: 1
IFC_Pset_Strat_Detail_Align - ExternalFace: 1
IFC_Pset_Caractéristiques - ID: 367501; Numérotation: 0592; Numéro niveau: 03; Titre niveau: Rez-de-chaussée; Stratigraphie: default [205,00]; Épaisseur: 20.5 cm; Épaisseur VARIABLE: no
IFC_Pset_Caractéristiques_FRUIT - Fruit: no; Taille: 0 cm
IFC_Pset_Géométrie - Forme en Élévation: rectangle; Longueur: 143.379 cm; Hauteur: 447.783 cm; Cote: 0.0128504 cm
IFC_Pset_Géométrie_P1 (POINT initial) - Hauteur: 447.783 cm; Cote: 0.0128504 cm; Angle XY: 90.1355 deg
IFC_Pset_Géométrie_P2 (POINT final) - Hauteur: 447.783 cm; Cote: 0.0128504 cm; Angle XY: 270.136 deg
IFC_Pset_Système de Référence Altimétrique_SUPÉRIEUR - NIVEAU: HAUT Rez-de-chaussée (Niveau 1 2343); delta: -30 cm; delta (P1): -30 cm; delta (P2): -30 cm; sous Niveau: <aucun>
IFC_Pset_Système de Référence Altimétrique_INFÉRIEUR - NIVEAU: Rez-de-chaussée (Rez-de-chaussée 1047); delta: 0.0128504 cm; delta (P1): 0.0128504 cm; delta (P2): 0.0128504 cm; sous Niveau: <aucun>
IFC_Pset_Données Métré - Longueur Pied: 143.4 cm; Longueur Tête: 143.4 cm; Hauteur Maximale: 447.8 cm; Hauteur Minimale: 447.8 cm; Surface en Plan: 3000 cm2; Surface Pied: 3000 cm2; Surface Tête: 3000 cm2; Surface de la Paroi: 64200 cm2; Volume: 1350000 cm3
IFC_Pset_Matériaux - Face gauche: Ivoire clair; Face droite: Ivoire clair; Face latérale: Ivoire clair
Pset_WallCommon - Reference: default [205,00] (..\VERTICALES\Default\)
BaseQuantities - GrossVolume: 1316150 cm3; NetVolume: 859208 cm3; NominalLength: 143.379 cm; NominalWidth: 20.5 cm; NominalHeight: 447.783 cm; GrossFootprintArea: 2939.26 cm2; NetFootprintArea: 2939.26 cm2; GrossSideArea: 64202.5 cm2; NetSideArea: 41912.6 cm2

# IfcWallStandardCase: default 220, Enveloppe 94515
In: Niveau 1
Type - Material: <aucun> 22 cm
Description: Enveloppe; Group: ...de stratigraphies = default; ...de matériaux et couleurs = Ivoire clair; ...de matériaux et couleurs - 1 = Ivoire clair; ...de matériaux et couleurs - 2 = Ivoire clair
__RECOGNIZE__ - ID: 94515; TPLG: 366; TPLG_OD: 9000; GENERATE: 1
CTLG_EXTERNAL_LINK - 0, DocType: 2; 0, Tag: 0; 0, Crc: 1977773087; 1, DocType: 2; 1, Tag: 100; 1, Crc: 1977773087; 2, DocType: 2; 2, Tag: 200; 2, Crc: 1977773087; 3, DocType: 9; 3, Tag: 0; 3, Crc: 20605473
IFC_PSET_PolygonOffset - polygonOffsetFactor: 2; polygonOffsetUnits: 2
IFC_Pset_Alignment - Alignment: 1
IFC_Pset_Strat_Detail_Align - ExternalFace: 0
IFC_Pset_Caractéristiques - ID: 94515; Numérotation: 0228; Numéro niveau: 04; Titre niveau: Niveau 1; Stratigraphie: default [220,00]; Épaisseur: 22 cm; Épaisseur VARIABLE: no
IFC_Pset_Caractéristiques_FRUIT - Fruit: no; Taille: 0 cm
IFC_Pset_Géométrie - Forme en Élévation: rectangle; Longueur: 206.879 cm; Hauteur: 376.102 cm; Cote: 0.0128504 cm
IFC_Pset_Géométrie_P1 (POINT initial) - Hauteur: 376.102 cm; Cote: 0.0128504 cm; Angle XY: 0.263809 deg
IFC_Pset_Géométrie_P2 (POINT final) - Hauteur: 376.102 cm; Cote: 0.0128504 cm; Angle XY: 180.264 deg
IFC_Pset_Système de Référence Altimétrique_SUPÉRIEUR - NIVEAU: HAUT Niveau 1 (Niveau 2 13545); delta: 0 cm; delta (P1): 0 cm; delta (P2): 0 cm; sous Niveau: <aucun>
IFC_Pset_Système de Référence Altimétrique_INFÉRIEUR - NIVEAU: Niveau 1 (Niveau 1 2343); delta: 0.0128504 cm; delta (P1): 0.0128504 cm; delta (P2): 0.0128504 cm; sous Niveau: <aucun>
IFC_Pset_Données Métré - Longueur Pied: 206.9 cm; Longueur Tête: 206.9 cm; Hauteur Maximale: 376.1 cm; Hauteur Minimale: 376.1 cm; Surface en Plan: 4600 cm2; Surface Pied: 4600 cm2; Surface Tête: 4600 cm2; Surface de la Paroi: 77800 cm2; Volume: 1710000 cm3
IFC_Pset_Matériaux - Face gauche: Ivoire clair; Face droite: Ivoire clair; Face latérale: Ivoire clair
Pset_WallCommon - Reference: default [220,00] (..\VERTICALES\Default\)
BaseQuantities - GrossVolume: 1711769 cm3; NetVolume: 1711769 cm3; NominalLength: 206.879 cm; NominalWidth: 22 cm; NominalHeight: 376.102 cm; GrossFootprintArea: 4551.34 cm2; NetFootprintArea: 4551.34 cm2; GrossSideArea: 77807.7 cm2; NetSideArea: 77807.7 cm2

# IfcWallStandardCase: default 230 (2)
Type - Material: <aucun> 23 cm
Description: Enveloppe; Group: ...de stratigraphies = default; ...de matériaux et couleurs = Ivoire clair; ...de matériaux et couleurs - 1 = Ivoire clair; ...de matériaux et couleurs - 2 = Ivoire clair
__RECOGNIZE__ - TPLG: 366; TPLG_OD: 9000; GENERATE: 1
CTLG_EXTERNAL_LINK - 0, DocType: 2; 0, Tag: 0; 0, Crc: 1977773087; 1, DocType: 2; 1, Tag: 100; 1, Crc: 1977773087; 2, DocType: 2; 2, Tag: 200; 2, Crc: 1977773087; 3, DocType: 9; 3, Tag: 0; 3, Crc: 1404885413
IFC_PSET_PolygonOffset - polygonOffsetFactor: 2; polygonOffsetUnits: 2
IFC_Pset_Strat_Detail_Align - ExternalFace: 0
IFC_Pset_Caractéristiques - Stratigraphie: default [230,00]; Épaisseur: 23 cm; Épaisseur VARIABLE: yes
IFC_Pset_Caractéristiques_FRUIT - Fruit: no; Taille: 0 cm
IFC_Pset_Géométrie - Forme en Élévation: rectangle; Cote: 0.0128504 cm
IFC_Pset_Géométrie_P1 (POINT initial) - Cote: 0.0128504 cm
IFC_Pset_Géométrie_P2 (POINT final) - Cote: 0.0128504 cm
IFC_Pset_Système de Référence Altimétrique_SUPÉRIEUR - sous Niveau: <aucun>
IFC_Pset_Système de Référence Altimétrique_INFÉRIEUR - delta: 0.0128504 cm; delta (P1): 0.0128504 cm; delta (P2): 0.0128504 cm; sous Niveau: <aucun>
IFC_Pset_Matériaux - Face gauche: Ivoire clair; Face droite: Ivoire clair; Face latérale: Ivoire clair
Pset_WallCommon - Reference: default [230,00] (..\VERTICALES\Default\)
Name | In | __RECOGNIZE__, ID = IFC_Pset_Caractéristiques, ID | Alignment | Numérotation | Numéro niveau | Titre niveau | Longueur (cm) = NominalLength (cm) | IFC_Pset_Géométrie, Hauteur (cm) = IFC_Pset_Géométrie_P1 (POINT initial), Hauteur (cm) = IFC_Pset_Géométrie_P2 (POINT final), Hauteur (cm) = NominalHeight (cm) | IFC_Pset_Géométrie_P1 (POINT initial), Angle XY (deg) | IFC_Pset_Géométrie_P2 (POINT final), Angle XY (deg) | IFC_Pset_Système de Référence Altimétrique_SUPÉRIEUR, NIVEAU | delta (cm) = delta (P1) (cm) = delta (P2) (cm) | IFC_Pset_Système de Référence Altimétrique_INFÉRIEUR, NIVEAU | Longueur Pied (cm) = Longueur Tête (cm) | Hauteur Maximale (cm) = Hauteur Minimale (cm) | Surface en Plan (cm2) = Surface Pied (cm2) = Surface Tête (cm2) | Surface de la Paroi (cm2) | Volume (cm3) | GrossVolume (cm3) = NetVolume (cm3) | NominalWidth (cm) | GrossFootprintArea (cm2) = NetFootprintArea (cm2) | GrossSideArea (cm2) = NetSideArea (cm2)
Enveloppe 2373 | Rez-de-chaussée | 2373 | 1 | 0001 | 03 | Rez-de-chaussée | 421.78 | 477.795 | 0.419213 | 180.419 | HAUT Rez-de-chaussée (Niveau 1 2343) | 0.0128504 | Rez-de-chaussée (Rez-de-chaussée 1047) | 421.7 | 477.8 | 9900 | 201500 | 4840000 | 4718286 | 23.4129 | 9875.12 | 201525
Enveloppe 94355 | Niveau 1 | 94355 | 0 | 0227 | 04 | Niveau 1 | 51.4521 | 376.102 | 141.778 | 321.778 | HAUT Niveau 1 (Niveau 2 13545) | 0 | Niveau 1 (Niveau 1 2343) | 51.5 | 376.1 | 1200 | 19400 | 460000 | 462501 | 23.9004 | 1229.72 | 19351.2

# IfcWallStandardCase: default 235 (2)
Type - Material: <aucun> 23.5 cm
Description: Enveloppe; Group: ...de stratigraphies = default; ...de matériaux et couleurs = Ivoire clair; ...de matériaux et couleurs - 1 = Ivoire clair; ...de matériaux et couleurs - 2 = Ivoire clair
__RECOGNIZE__ - TPLG: 366; TPLG_OD: 9000; GENERATE: 1
CTLG_EXTERNAL_LINK - 0, DocType: 2; 0, Tag: 0; 0, Crc: 1977773087; 1, DocType: 2; 1, Tag: 100; 1, Crc: 1977773087; 2, DocType: 2; 2, Tag: 200; 2, Crc: 1977773087; 3, DocType: 9; 3, Tag: 0; 3, Crc: -675992823
IFC_PSET_PolygonOffset - polygonOffsetFactor: 2; polygonOffsetUnits: 2
IFC_Pset_Alignment - Alignment: 1
IFC_Pset_Strat_Detail_Align - ExternalFace: 0
IFC_Pset_Caractéristiques - Stratigraphie: default [235,00]; Épaisseur: 23.5 cm
IFC_Pset_Caractéristiques_FRUIT - Fruit: no; Taille: 0 cm
IFC_Pset_Géométrie - Forme en Élévation: rectangle; Cote: 0.0128504 cm
IFC_Pset_Géométrie_P1 (POINT initial) - Cote: 0.0128504 cm
IFC_Pset_Géométrie_P2 (POINT final) - Cote: 0.0128504 cm
IFC_Pset_Système de Référence Altimétrique_SUPÉRIEUR - sous Niveau: <aucun>
IFC_Pset_Système de Référence Altimétrique_INFÉRIEUR - delta: 0.0128504 cm; delta (P1): 0.0128504 cm; delta (P2): 0.0128504 cm; sous Niveau: <aucun>
IFC_Pset_Données Métré - Longueur Pied: 132.4 cm; Longueur Tête: 132.4 cm; Surface en Plan: 3200 cm2; Surface Pied: 3200 cm2; Surface Tête: 3200 cm2
IFC_Pset_Matériaux - Face gauche: Ivoire clair; Face droite: Ivoire clair; Face latérale: Ivoire clair
Pset_WallCommon - Reference: default [235,00] (..\VERTICALES\Default\)
BaseQuantities - NominalWidth: 23.5 cm
Name | In | __RECOGNIZE__, ID = IFC_Pset_Caractéristiques, ID | Numérotation | Numéro niveau | Titre niveau | Épaisseur VARIABLE | Longueur (cm) = NominalLength (cm) | IFC_Pset_Géométrie, Hauteur (cm) = IFC_Pset_Géométrie_P1 (POINT initial), Hauteur (cm) = IFC_Pset_Géométrie_P2 (POINT final), Hauteur (cm) = NominalHeight (cm) | IFC_Pset_Géométrie_P1 (POINT initial), Angle XY (deg) | IFC_Pset_Géométrie_P2 (POINT final), Angle XY (deg) | IFC_Pset_Système de Référence Altimétrique_SUPÉRIEUR, NIVEAU | delta (cm) = delta (P1) (cm) = delta (P2) (cm) | IFC_Pset_Système de Référence Altimétrique_INFÉRIEUR, NIVEAU | Hauteur Maximale (cm) = Hauteur Minimale (cm) | Surface de la Paroi (cm2) | Volume (cm3) | GrossVolume (cm3) = NetVolume (cm3) | GrossFootprintArea (cm2) = NetFootprintArea (cm2) | GrossSideArea (cm2) = NetSideArea (cm2)
Enveloppe 2494 | Rez-de-chaussée | 2494 | 0003 | 03 | Rez-de-chaussée | no | 132.412 | 477.795 | 89.7527 | 269.753 | HAUT Rez-de-chaussée (Niveau 1 2343) | 0.0128504 | Rez-de-chaussée (Rez-de-chaussée 1047) | 477.8 | 63300 | 1520000 | 1486751 | 3111.69 | 63266
Enveloppe 94341 | Niveau 1 | 94341 | 0225 | 04 | Niveau 1 | yes | 132.392 | 376.102 | 90.775 | 270.775 | HAUT Niveau 1 (Niveau 2 13545) | 0 | Niveau 1 (Niveau 1 2343) | 376.1 | 49800 | 1200000 | 1170135 | 3111.22 | 49793

# IfcWallStandardCase: default 240 (3)
In: Rez-de-Jardin
Type - Material: <aucun> 24 cm
__RECOGNIZE__ - GENERATE: 1
CTLG_EXTERNAL_LINK - 0, DocType: 2; 0, Tag: 0; 1, DocType: 2; 1, Tag: 100; 2, DocType: 2; 2, Tag: 200; 3, DocType: 9; 3, Tag: 0; 3, Crc: -61664470
IFC_PSET_PolygonOffset - polygonOffsetFactor: 2; polygonOffsetUnits: 2
IFC_Pset_Alignment - Alignment: 1
IFC_Pset_Caractéristiques - Numéro niveau: 02; Titre niveau: Rez-de-Jardin; Stratigraphie: default [240,00]; Épaisseur: 24 cm; Épaisseur VARIABLE: no
IFC_Pset_Caractéristiques_FRUIT - Fruit: no; Taille: 0 cm
IFC_Pset_Système de Référence Altimétrique_SUPÉRIEUR - NIVEAU: HAUT Rez-de-Jardin (Rez-de-chaussée 1047); sous Niveau: <aucun>
IFC_Pset_Système de Référence Altimétrique_INFÉRIEUR - NIVEAU: Rez-de-Jardin (Rez-de-Jardin 15545); sous Niveau: <aucun>
Pset_WallCommon - Reference: default [240,00] (..\VERTICALES\Default\)
Name | Description | __RECOGNIZE__, ID = IFC_Pset_Caractéristiques, ID | TPLG | TPLG_OD | 0, Crc = 1, Crc = 2, Crc | ExternalFace | Numérotation | Forme en Élévation | Longueur (cm) = NominalLength (cm) | IFC_Pset_Géométrie, Hauteur (cm) = IFC_Pset_Géométrie_P1 (POINT initial), Hauteur (cm) | IFC_Pset_Géométrie, Cote (cm) = IFC_Pset_Géométrie_P1 (POINT initial), Cote (cm) = IFC_Pset_Géométrie_P2 (POINT final), Cote (cm) = IFC_Pset_Système de Référence Altimétrique_INFÉRIEUR, delta (cm) = IFC_Pset_Système de Référence Altimétrique_INFÉRIEUR, delta (P1) (cm) = IFC_Pset_Système de Référence Altimétrique_INFÉRIEUR, delta (P2) (cm) | IFC_Pset_Géométrie_P1 (POINT initial), Angle XY (deg) | IFC_Pset_Géométrie_P2 (POINT final), Hauteur (cm) | IFC_Pset_Géométrie_P2 (POINT final), Angle XY (deg) | IFC_Pset_Système de Référence Altimétrique_SUPÉRIEUR, delta (cm) = IFC_Pset_Système de Référence Altimétrique_SUPÉRIEUR, delta (P1) (cm) = IFC_Pset_Système de Référence Altimétrique_SUPÉRIEUR, delta (P2) (cm) | Longueur Pied (cm) | Longueur Tête (cm) | Hauteur Maximale (cm) | Hauteur Minimale (cm) | Surface en Plan (cm2) | Surface Pied (cm2) | Surface Tête (cm2) | Surface de la Paroi (cm2) | Volume (cm3) | Face gauche = Face droite = Face latérale | GrossVolume (cm3) = NetVolume (cm3) | NominalWidth (cm) | NominalHeight (cm) | GrossFootprintArea (cm2) = NetFootprintArea (cm2) | GrossSideArea (cm2) = NetSideArea (cm2) | Group | Rayon (cm) | Point arc | Centre | Angle de la Tangente (deg)
Enveloppe 310519 | Enveloppe | 310519 | 366 | 9000 | 1977773087 | 1 | 0545 | rectangle | 91.0177 | 201.4 | -1.94511e-11 | 179.839 | 201.4 | 359.839 | -90 | 91 | 91 | 201.4 | 201.4 | 2200 | 2200 | 2200 | 18300 | 440000 | Ivoire clair | 439944 | 24 | 201.4 | 2184.43 | 18331 | ...de stratigraphies = default; ...de matériaux et couleurs = Ivoire clair; ...de matériaux et couleurs - 1 = Ivoire clair; ...de matériaux et couleurs - 2 = Ivoire clair
Enveloppe courbe 336805 | Enveloppe courbe | 336805 | 367 | 9001 | -746779066 | 0 | 46 | trapèze | 54.2315 | 221.503 | 1.33227e-13 | 32.2503 | 249.812 | 212.25 | 0 | 54.2 | 61.1 | 249.8 | 221.5 | 800 | 1300 | 1500 | 12800 | 310000 | Blanc | 304905 | 23.8579 | 235.657 | 1293.85 | 12780 | ...de matériaux et couleurs = Blanc; ...de matériaux et couleurs - 1 = Blanc; ...de matériaux et couleurs - 2 = Blanc; ...de stratigraphies = default | 96.3473 | [-424,2; -1 176,5] cm | [-508,8; -1 108,9] cm | 22.9679
Enveloppe courbe 336582 | Enveloppe courbe | 336582 | 367 | 9001 | -746779066 | 0 | 45 | trapèze | 42.8727 | 249.812 | 8.88178e-14 | 28.3679 | 270.392 | 208.368 | 0 | 42.9 | 47.6 | 270.4 | 249.8 | 700 | 1000 | 1100 | 11200 | 270000 | Blanc | 265645 | 23.8219 | 260.102 | 1021.31 | 11151.3 | ...de matériaux et couleurs = Blanc; ...de matériaux et couleurs - 1 = Blanc; ...de matériaux et couleurs - 2 = Blanc; ...de stratigraphies = default | 86.5919 | [-401,3; -1 128,3] cm | [-497,8; -1 108,1] cm | 21.0267

# IfcWallStandardCase: default 245, Enveloppe 452462
In: Rez-de-Jardin
Type - Material: <aucun> 24.5 cm
Description: Enveloppe; Group: ...de stratigraphies = default; ...de matériaux et couleurs = Ivoire clair; ...de matériaux et couleurs - 1 = Ivoire clair; ...de matériaux et couleurs - 2 = Ivoire clair
__RECOGNIZE__ - ID: 452462; TPLG: 366; TPLG_OD: 9000; GENERATE: 1
CTLG_EXTERNAL_LINK - 0, DocType: 2; 0, Tag: 0; 0, Crc: 1977773087; 1, DocType: 2; 1, Tag: 100; 1, Crc: 1977773087; 2, DocType: 2; 2, Tag: 200; 2, Crc: 1977773087; 3, DocType: 9; 3, Tag: 0; 3, Crc: -119628326
IFC_PSET_PolygonOffset - polygonOffsetFactor: 2; polygonOffsetUnits: 2
IFC_Pset_Alignment - Alignment: 1
IFC_Pset_Strat_Detail_Align - ExternalFace: 1
IFC_Pset_Caractéristiques - ID: 452462; Numérotation: 0753; Numéro niveau: 02; Titre niveau: Rez-de-Jardin; Stratigraphie: default [245,00]; Épaisseur: 24.5 cm; Épaisseur VARIABLE: yes
IFC_Pset_Caractéristiques_FRUIT - Fruit: no; Taille: 0 cm
IFC_Pset_Géométrie - Forme en Élévation: rectangle; Longueur: 162.152 cm; Hauteur: 285.4 cm; Cote: 106 cm
IFC_Pset_Géométrie_P1 (POINT initial) - Hauteur: 285.4 cm; Cote: 106 cm; Angle XY: 45.1068 deg
IFC_Pset_Géométrie_P2 (POINT final) - Hauteur: 285.4 cm; Cote: 106 cm; Angle XY: 225.107 deg
IFC_Pset_Système de Référence Altimétrique_SUPÉRIEUR - NIVEAU: HAUT Rez-de-Jardin (Rez-de-chaussée 1047); delta: 100 cm; delta (P1): 100 cm; delta (P2): 100 cm; sous Niveau: <aucun>
IFC_Pset_Système de Référence Altimétrique_INFÉRIEUR - NIVEAU: Rez-de-Jardin (Rez-de-Jardin 15545); delta: 106 cm; delta (P1): 106 cm; delta (P2): 106 cm; sous Niveau: <aucun>
IFC_Pset_Données Métré - Longueur Pied: 162.2 cm; Longueur Tête: 162.2 cm; Hauteur Maximale: 285.4 cm; Hauteur Minimale: 285.4 cm; Surface en Plan: 4200 cm2; Surface Pied: 4200 cm2; Surface Tête: 4200 cm2; Surface de la Paroi: 46300 cm2; Volume: 1200000 cm3
IFC_Pset_Matériaux - Face gauche: Ivoire clair; Face droite: Ivoire clair; Face latérale: Ivoire clair
Pset_WallCommon - Reference: default [245,00] (..\VERTICALES\Default\)
BaseQuantities - GrossVolume: 1204321 cm3; NetVolume: 164834 cm3; NominalLength: 162.152 cm; NominalWidth: 26.0235 cm; NominalHeight: 285.4 cm; GrossFootprintArea: 4219.76 cm2; NetFootprintArea: 4219.76 cm2; GrossSideArea: 46278.1 cm2; NetSideArea: 6335.22 cm2

# IfcWallStandardCase: default 249 (4)
In: Niveau 1
Type - Material: <aucun> 24.9 cm
Description: Enveloppe; Group: ...de stratigraphies = default; ...de matériaux et couleurs = Ivoire clair; ...de matériaux et couleurs - 1 = Ivoire clair; ...de matériaux et couleurs - 2 = Ivoire clair
__RECOGNIZE__ - TPLG: 366; TPLG_OD: 9000; GENERATE: 1
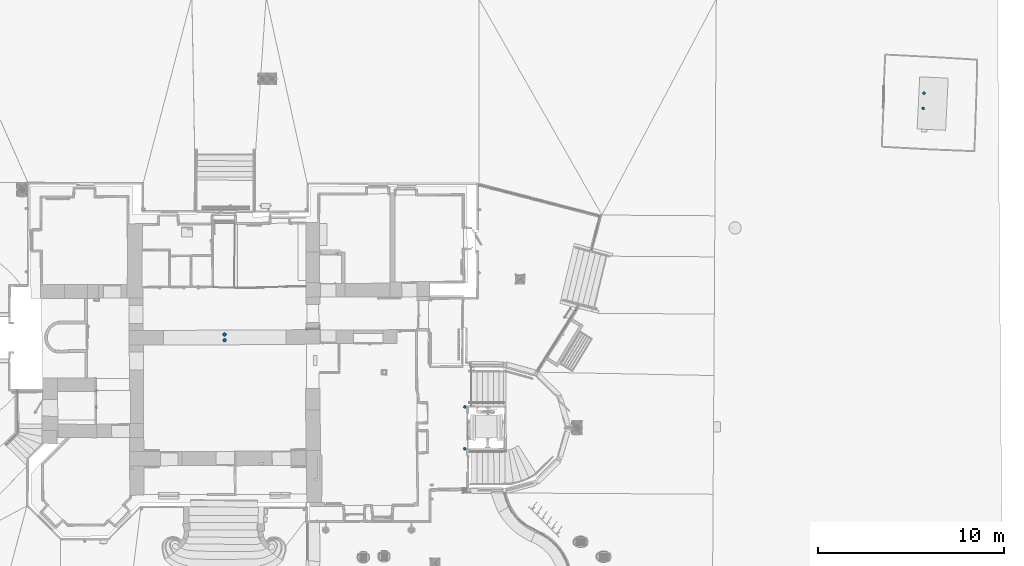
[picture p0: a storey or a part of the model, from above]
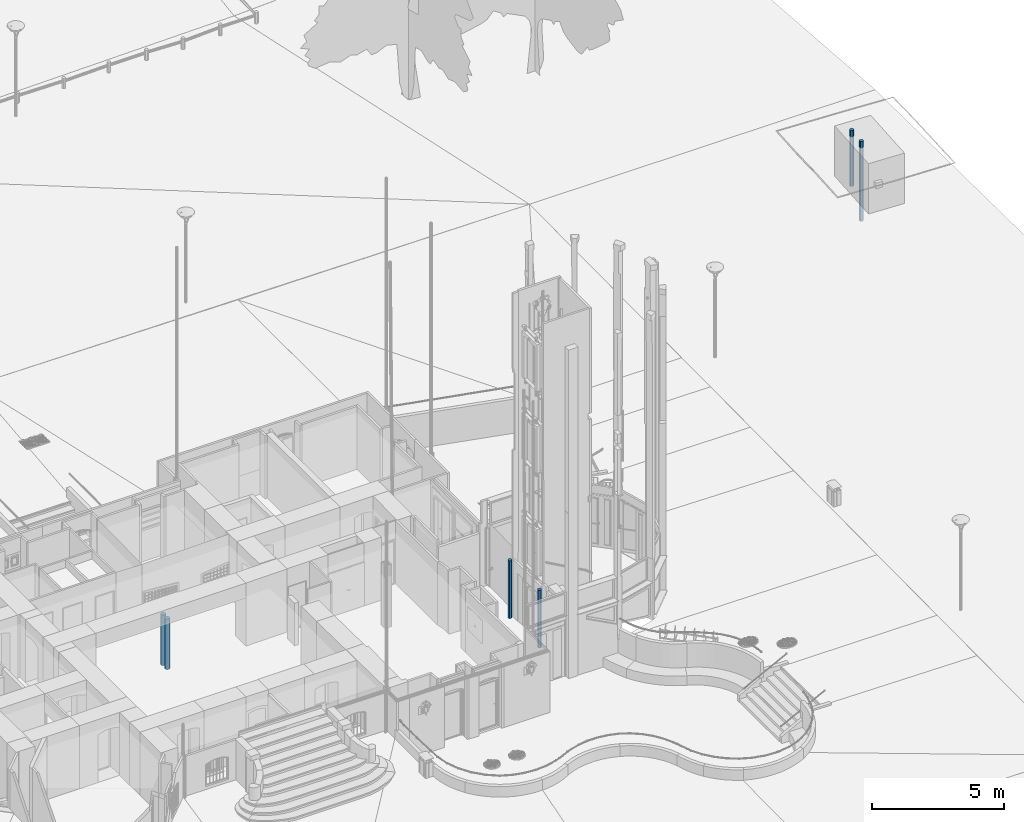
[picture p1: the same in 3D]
Properties of the parts of a building model (IFC2X3), part 23 of 37

# IfcWallStandardCase: default 249 (4)
CTLG_EXTERNAL_LINK - 0, DocType: 2; 0, Tag: 0; 0, Crc: 1977773087; 1, DocType: 2; 1, Tag: 100; 1, Crc: 1977773087; 2, DocType: 2; 2, Tag: 200; 2, Crc: 1977773087; 3, DocType: 9; 3, Tag: 0; 3, Crc: -541422725
IFC_PSET_PolygonOffset - polygonOffsetFactor: 2; polygonOffsetUnits: 2
IFC_Pset_Alignment - Alignment: 1
IFC_Pset_Strat_Detail_Align - ExternalFace: 1
IFC_Pset_Caractéristiques - Numéro niveau: 04; Titre niveau: Niveau 1; Stratigraphie: default [249,00]; Épaisseur: 24.9 cm; Épaisseur VARIABLE: no
IFC_Pset_Caractéristiques_FRUIT - Fruit: no; Taille: 0 cm
IFC_Pset_Géométrie - Forme en Élévation: rectangle; Longueur: 160.209 cm; Hauteur: 82.1022 cm; Cote: 0.0128504 cm
IFC_Pset_Géométrie_P1 (POINT initial) - Hauteur: 82.1022 cm; Cote: 0.0128504 cm; Angle XY: 0 deg
IFC_Pset_Géométrie_P2 (POINT final) - Hauteur: 82.1022 cm; Cote: 0.0128504 cm; Angle XY: 180 deg
IFC_Pset_Système de Référence Altimétrique_SUPÉRIEUR - NIVEAU: HAUT Niveau 1 (Niveau 2 13545); delta: -294 cm; delta (P1): -294 cm; delta (P2): -294 cm; sous Niveau: <aucun>
IFC_Pset_Système de Référence Altimétrique_INFÉRIEUR - NIVEAU: Niveau 1 (Niveau 1 2343); delta: 0.0128504 cm; delta (P1): 0.0128504 cm; delta (P2): 0.0128504 cm; sous Niveau: <aucun>
IFC_Pset_Données Métré - Longueur Pied: 160.2 cm; Longueur Tête: 160.2 cm; Hauteur Maximale: 82.1 cm; Hauteur Minimale: 82.1 cm; Surface en Plan: 4000 cm2; Surface Pied: 4000 cm2; Surface Tête: 4000 cm2; Surface de la Paroi: 13200 cm2; Volume: 330000 cm3
IFC_Pset_Matériaux - Face gauche: Ivoire clair; Face droite: Ivoire clair; Face latérale: Ivoire clair
Pset_WallCommon - Reference: default [249,00] (..\VERTICALES\Default\)
BaseQuantities - GrossVolume: 327523 cm3; NetVolume: 250121 cm3; NominalLength: 160.209 cm; NominalWidth: 24.9 cm; NominalHeight: 82.1022 cm; GrossFootprintArea: 3989.21 cm2; NetFootprintArea: 3989.21 cm2; GrossSideArea: 13153.5 cm2; NetSideArea: 10045 cm2
Name | __RECOGNIZE__, ID = IFC_Pset_Caractéristiques, ID | Numérotation
Enveloppe 442722 | 442722 | 0744
Enveloppe 449481 | 449481 | 0748
Enveloppe 449443 | 449443 | 0746
Enveloppe 449458 | 449458 | 0747

# IfcWallStandardCase: default 250 (6)
Type - Material: <aucun> 25 cm
__RECOGNIZE__ - GENERATE: 1
CTLG_EXTERNAL_LINK - 0, DocType: 2; 0, Tag: 0; 1, DocType: 2; 1, Tag: 100; 2, DocType: 2; 2, Tag: 200; 3, DocType: 9; 3, Tag: 0; 3, Crc: 1541080003
IFC_PSET_PolygonOffset - polygonOffsetFactor: 2; polygonOffsetUnits: 2
IFC_Pset_Caractéristiques - Stratigraphie: default [250,00]; Épaisseur: 25 cm
IFC_Pset_Caractéristiques_FRUIT - Fruit: no; Taille: 0 cm
IFC_Pset_Système de Référence Altimétrique_SUPÉRIEUR - sous Niveau: <aucun>
IFC_Pset_Système de Référence Altimétrique_INFÉRIEUR - sous Niveau: <aucun>
Pset_WallCommon - Reference: default [250,00] (..\VERTICALES\Default\)
Name | In | Description | __RECOGNIZE__, ID = IFC_Pset_Caractéristiques, ID | TPLG | TPLG_OD | 0, Crc = 1, Crc = 2, Crc | Alignment | ExternalFace | Numérotation | Numéro niveau | Titre niveau | Épaisseur VARIABLE | Forme en Élévation | Longueur (cm) = NominalLength (cm) | IFC_Pset_Géométrie, Hauteur (cm) = IFC_Pset_Géométrie_P1 (POINT initial), Hauteur (cm) | IFC_Pset_Géométrie, Cote (cm) = IFC_Pset_Géométrie_P1 (POINT initial), Cote (cm) = IFC_Pset_Géométrie_P2 (POINT final), Cote (cm) = IFC_Pset_Système de Référence Altimétrique_INFÉRIEUR, delta (cm) = IFC_Pset_Système de Référence Altimétrique_INFÉRIEUR, delta (P1) (cm) = IFC_Pset_Système de Référence Altimétrique_INFÉRIEUR, delta (P2) (cm) | IFC_Pset_Géométrie_P1 (POINT initial), Angle XY (deg) | IFC_Pset_Géométrie_P2 (POINT final), Hauteur (cm) | IFC_Pset_Géométrie_P2 (POINT final), Angle XY (deg) | IFC_Pset_Système de Référence Altimétrique_SUPÉRIEUR, NIVEAU | IFC_Pset_Système de Référence Altimétrique_SUPÉRIEUR, delta (cm) = IFC_Pset_Système de Référence Altimétrique_SUPÉRIEUR, delta (P1) (cm) = IFC_Pset_Système de Référence Altimétrique_SUPÉRIEUR, delta (P2) (cm) | IFC_Pset_Système de Référence Altimétrique_INFÉRIEUR, NIVEAU | Longueur Pied (cm) | Longueur Tête (cm) | Hauteur Maximale (cm) | Hauteur Minimale (cm) | Surface en Plan (cm2) | Surface Pied (cm2) | Surface Tête (cm2) | Surface de la Paroi (cm2) | Volume (cm3) | Face gauche = Face droite = Face latérale | GrossVolume (cm3) | NetVolume (cm3) | NominalWidth (cm) | NominalHeight (cm) | GrossFootprintArea (cm2) = NetFootprintArea (cm2) | GrossSideArea (cm2) | NetSideArea (cm2) | Group
Enveloppe 452367 | Rez-de-Jardin | Enveloppe | 452367 | 366 | 9000 | 1977773087 | 1 | 1 | 0752 | 02 | Rez-de-Jardin | yes | rectangle | 163.609 | 285.4 | 106 | 15.0092 | 285.4 | 195.009 | HAUT Rez-de-Jardin (Rez-de-chaussée 1047) | 100 | Rez-de-Jardin (Rez-de-Jardin 15545) | 163.6 | 163.6 | 285.4 | 285.4 | 4200 | 4200 | 4200 | 46700 | 1210000 | Ivoire clair | 1212062 | 265656 | 25.9575 | 285.4 | 4246.88 | 46694.1 | 10256.5 | ...de stratigraphies = default; ...de matériaux et couleurs = Ivoire clair; ...de matériaux et couleurs - 1 = Ivoire clair; ...de matériaux et couleurs - 2 = Ivoire clair
Enveloppe 311643 | Rez-de-Jardin | Enveloppe | 311643 | 366 | 9000 | 1977773087 | 0 | 1 | 0549 | 02 | Rez-de-Jardin | no | rectangle | 89.7978 | 201.4 | -1.94511e-11 | 179.683 | 201.4 | 359.683 | HAUT Rez-de-Jardin (Rez-de-chaussée 1047) | -90 | Rez-de-Jardin (Rez-de-Jardin 15545) | 89.8 | 89.8 | 201.4 | 201.4 | 2200 | 2200 | 2200 | 18100 | 450000 | Ivoire clair | 452133 | 452133 | 25 | 201.4 | 2244.95 | 18085.3 | 18085.3 | ...de stratigraphies = default; ...de matériaux et couleurs = Ivoire clair; ...de matériaux et couleurs - 1 = Ivoire clair; ...de matériaux et couleurs - 2 = Ivoire clair
Enveloppe courbe 328920 | Rez-de-Jardin | Enveloppe courbe | 328920 | 367 | 9001 | -746779066 | 0 | 0 | 44 | 02 | Rez-de-Jardin | no | trapèze | 70.2128 | 222.087 | 8.88178e-14 | 45.9802 | 255.109 | 225.98 | HAUT Rez-de-Jardin (Rez-de-chaussée 1047) | 0 | Rez-de-Jardin (Rez-de-Jardin 15545) | 70.2 | 77.6 | 255.1 | 222.1 | 1100 | 1700 | 1900 | 16700 | 420000 | Blanc | 415455 | 415455 | 24.7994 | 238.598 | 1741.23 | 16752.7 | 16752.7 | ...de matériaux et couleurs = Blanc; ...de matériaux et couleurs - 1 = Blanc; ...de matériaux et couleurs - 2 = Blanc; ...de stratigraphies = default | IFC_Pset_Géométrie - Rayon: 87.4919 cm; Point arc: [-3,8; -1 174,6] cm; Centre: [76,8; -1 115,4] cm; Angle de la Tangente: 30.1151 deg
Enveloppe courbe 328787 | Rez-de-Jardin | Enveloppe courbe | 328787 | 367 | 9001 | -746779066 | 0 | 0 | 43 | 02 | Rez-de-Jardin | no | trapèze | 34.8065 | 254.304 | 8.88178e-14 | 8.61014 | 270.392 | 188.61 | HAUT Rez-de-Jardin (Rez-de-chaussée 1047) | 0 | Rez-de-Jardin (Rez-de-Jardin 15545) | 34.8 | 38.4 | 270.4 | 254.3 | 600 | 900 | 1000 | 9100 | 230000 | Blanc | 227958 | 227958 | 24.9642 | 262.348 | 868.915 | 9131.41 | 9131.41 | ...de matériaux et couleurs = Blanc; ...de matériaux et couleurs - 1 = Blanc; ...de matériaux et couleurs - 2 = Blanc; ...de stratigraphies = default | IFC_Pset_Géométrie - Rayon: 231.618 cm; Point arc: [-24,1; -1 120,7] cm; Centre: [216,8; -1 081,2] cm; Angle de la Tangente: 11.4301 deg
Enveloppe 722381 | Rez-de-chaussée | Enveloppe | 722381 | 366 | 9000 | 1977773087 | 0 | 0 | 1059 | 03 | Rez-de-chaussée | no | rectangle | 20.2732 | 1228.79 | 0.0128504 | 89.7122 | 1228.79 | 269.712 | Couverture (Couverture 2134) | -139.811 | Rez-de-chaussée (Rez-de-chaussée 1047) | 20.3 | 20.3 | 1228.8 | 1228.8 | 500 | 500 | 500 | 24900 | 620000 | Ivoire clair | 622786 | 622786 | 25 | 1228.79 | 506.829 | 24911.4 | 24911.4 | ...de stratigraphies = default; ...de matériaux et couleurs = Ivoire clair; ...de matériaux et couleurs - 1 = Ivoire clair; ...de matériaux et couleurs - 2 = Ivoire clair
Enveloppe 1007136 | Couverture | Enveloppe | 1007136 | 366 | 9000 | 1977773087 | 1 | 0 | 1151 | 07 | Couverture | no | rectangle | 25.3737 | 141.2 | -279.702 | 89.4192 | 141.2 | 269.419 | (Couverture 2134 <aucun>) | -138.502 | Couverture (Couverture 2134) | 25.4 | 25.4 | 141.2 | 141.2 | 600 | 600 | 600 | 3600 | 90000 | Ivoire clair | 89569.3 | 89569.3 | 25 | 141.2 | 634.343 | 3582.77 | 3582.77 | ...de stratigraphies = default; ...de matériaux et couleurs = Ivoire clair; ...de matériaux et couleurs - 1 = Ivoire clair; ...de matériaux et couleurs - 2 = Ivoire clair

# IfcWallStandardCase: default 255 (6)
Type - Material: <aucun> 25.5 cm
Description: Enveloppe; Group: ...de stratigraphies = default; ...de matériaux et couleurs = Ivoire clair; ...de matériaux et couleurs - 1 = Ivoire clair; ...de matériaux et couleurs - 2 = Ivoire clair
__RECOGNIZE__ - TPLG: 366; TPLG_OD: 9000; GENERATE: 1
CTLG_EXTERNAL_LINK - 0, DocType: 2; 0, Tag: 0; 0, Crc: 1977773087; 1, DocType: 2; 1, Tag: 100; 1, Crc: 1977773087; 2, DocType: 2; 2, Tag: 200; 2, Crc: 1977773087; 3, DocType: 9; 3, Tag: 0; 3, Crc: 2051339170
IFC_PSET_PolygonOffset - polygonOffsetFactor: 2; polygonOffsetUnits: 2
IFC_Pset_Alignment - Alignment: 0
IFC_Pset_Strat_Detail_Align - ExternalFace: 0
IFC_Pset_Caractéristiques - Stratigraphie: default [255,00]; Épaisseur: 25.5 cm; Épaisseur VARIABLE: no
IFC_Pset_Caractéristiques_FRUIT - Fruit: no; Taille: 0 cm
IFC_Pset_Géométrie - Forme en Élévation: rectangle
IFC_Pset_Système de Référence Altimétrique_SUPÉRIEUR - sous Niveau: <aucun>
IFC_Pset_Système de Référence Altimétrique_INFÉRIEUR - sous Niveau: <aucun>
IFC_Pset_Matériaux - Face gauche: Ivoire clair; Face droite: Ivoire clair; Face latérale: Ivoire clair
Pset_WallCommon - Reference: default [255,00] (..\VERTICALES\Default\)
BaseQuantities - NominalWidth: 25.5 cm
Name | In | __RECOGNIZE__, ID = IFC_Pset_Caractéristiques, ID | Numérotation | Numéro niveau | Titre niveau | Longueur (cm) = NominalLength (cm) | IFC_Pset_Géométrie, Hauteur (cm) = IFC_Pset_Géométrie_P1 (POINT initial), Hauteur (cm) = IFC_Pset_Géométrie_P2 (POINT final), Hauteur (cm) = NominalHeight (cm) | IFC_Pset_Géométrie, Cote (cm) = IFC_Pset_Géométrie_P1 (POINT initial), Cote (cm) = IFC_Pset_Géométrie_P2 (POINT final), Cote (cm) = IFC_Pset_Système de Référence Altimétrique_INFÉRIEUR, delta (cm) = IFC_Pset_Système de Référence Altimétrique_INFÉRIEUR, delta (P1) (cm) = IFC_Pset_Système de Référence Altimétrique_INFÉRIEUR, delta (P2) (cm) | IFC_Pset_Géométrie_P1 (POINT initial), Angle XY (deg) | IFC_Pset_Géométrie_P2 (POINT final), Angle XY (deg) | IFC_Pset_Système de Référence Altimétrique_SUPÉRIEUR, NIVEAU | IFC_Pset_Système de Référence Altimétrique_SUPÉRIEUR, delta (cm) = IFC_Pset_Système de Référence Altimétrique_SUPÉRIEUR, delta (P1) (cm) = IFC_Pset_Système de Référence Altimétrique_SUPÉRIEUR, delta (P2) (cm) | IFC_Pset_Système de Référence Altimétrique_INFÉRIEUR, NIVEAU | Longueur Pied (cm) = Longueur Tête (cm) | Hauteur Maximale (cm) = Hauteur Minimale (cm) | Surface en Plan (cm2) = Surface Pied (cm2) = Surface Tête (cm2) | Surface de la Paroi (cm2) | Volume (cm3) | GrossVolume (cm3) | NetVolume (cm3) | GrossFootprintArea (cm2) = NetFootprintArea (cm2) | GrossSideArea (cm2) | NetSideArea (cm2)
Enveloppe 728190 | Rez-de-chaussée | 728190 | 1064 | 03 | Rez-de-chaussée | 144.325 | 472.783 | 0.0128504 | 89.7122 | 269.712 | HAUT Rez-de-chaussée (Niveau 1 2343) | -5 | Rez-de-chaussée (Rez-de-chaussée 1047) | 144.3 | 472.8 | 3800 | 68200 | 1770000 | 1739973 | 144384 | 3680.28 | 68234.3 | 5662.13
Enveloppe 728194 | Rez-de-chaussée | 728194 | 1065 | 03 | Rez-de-chaussée | 165.492 | 472.783 | 0.0128504 | 89.5447 | 269.545 | HAUT Rez-de-chaussée (Niveau 1 2343) | -5 | Rez-de-chaussée (Rez-de-chaussée 1047) | 165.5 | 472.8 | 4300 | 78200 | 2030000 | 1995160 | 213638 | 4220.04 | 78241.6 | 8377.96
Enveloppe 728247 | Niveau 1 | 728247 | 1066 | 04 | Niveau 1 | 144.332 | 376.115 | -5 | 89.7122 | 269.712 | HAUT Niveau 1 (Niveau 2 13545) | -5 | Niveau 1 (Niveau 1 2343) | 144.3 | 376.1 | 3800 | 54300 | 1410000 | 1384278 | 77777.1 | 3680.46 | 54285.4 | 3050.08
Enveloppe 728252 | Niveau 1 | 728252 | 1067 | 04 | Niveau 1 | 165.691 | 376.115 | -5 | 89.311 | 269.311 | HAUT Niveau 1 (Niveau 2 13545) | -5 | Niveau 1 (Niveau 1 2343) | 165.7 | 376.1 | 4300 | 62300 | 1620000 | 1589128 | 282628 | 4225.11 | 62318.7 | 11083.4
Enveloppe 728289 | Niveau 2 | 728289 | 1068 | 05 | Niveau 2 | 144.325 | 240 | -5 | 89.7122 | 269.712 | HAUT Niveau 2 (Mezzanine 49003) | 1.33227e-11 | Niveau 2 (Niveau 2 13545) | 144.3 | 240 | 3800 | 34600 | 900000 | 883268 | 69639 | 3680.28 | 34638 | 2730.94
Enveloppe 728294 | Niveau 2 | 728294 | 1069 | 05 | Niveau 2 | 164.244 | 240 | -5 | 90.2749 | 270.275 | HAUT Niveau 2 (Mezzanine 49003) | 1.36779e-11 | Niveau 2 (Niveau 2 13545) | 164.2 | 240 | 4300 | 39400 | 1020000 | 1005170 | 79948 | 4188.21 | 39418.4 | 3135.22

# IfcWallStandardCase: default 259.083740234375, Enveloppe 2939
In: Rez-de-chaussée
Type - Material: <aucun> 25.9084 cm
Description: Enveloppe; Group: ...de stratigraphies = default; ...de matériaux et couleurs = Ivoire clair; ...de matériaux et couleurs - 1 = Ivoire clair; ...de matériaux et couleurs - 2 = Ivoire clair
__RECOGNIZE__ - ID: 2939; TPLG: 366; TPLG_OD: 9000; GENERATE: 1
CTLG_EXTERNAL_LINK - 0, DocType: 2; 0, Tag: 0; 0, Crc: 1977773087; 1, DocType: 2; 1, Tag: 100; 1, Crc: 1977773087; 2, DocType: 2; 2, Tag: 200; 2, Crc: 1977773087; 3, DocType: 9; 3, Tag: 0; 3, Crc: 617797264
IFC_PSET_PolygonOffset - polygonOffsetFactor: 2; polygonOffsetUnits: 2
IFC_Pset_Alignment - Alignment: 0
IFC_Pset_Strat_Detail_Align - ExternalFace: 0
IFC_Pset_Caractéristiques - ID: 2939; Numérotation: 0015; Numéro niveau: 03; Titre niveau: Rez-de-chaussée; Stratigraphie: default [259,08]; Épaisseur: 25.91 cm; Épaisseur VARIABLE: no
IFC_Pset_Caractéristiques_FRUIT - Fruit: no; Taille: 0 cm
IFC_Pset_Géométrie - Forme en Élévation: rectangle; Longueur: 185.192 cm; Hauteur: 399.097 cm; Cote: 0.0128504 cm
IFC_Pset_Géométrie_P1 (POINT initial) - Hauteur: 399.097 cm; Cote: 0.0128504 cm; Angle XY: 0.0110109 deg
IFC_Pset_Géométrie_P2 (POINT final) - Hauteur: 399.097 cm; Cote: 0.0128504 cm; Angle XY: 180.011 deg
IFC_Pset_Système de Référence Altimétrique_SUPÉRIEUR - NIVEAU: HAUT Rez-de-chaussée (Niveau 1 2343); delta: -78.6853 cm; delta (P1): -78.6853 cm; delta (P2): -78.6853 cm; sous Niveau: <aucun>
IFC_Pset_Système de Référence Altimétrique_INFÉRIEUR - NIVEAU: Rez-de-chaussée (Rez-de-chaussée 1047); delta: 0.0128504 cm; delta (P1): 0.0128504 cm; delta (P2): 0.0128504 cm; sous Niveau: <aucun>
IFC_Pset_Données Métré - Longueur Pied: 185.2 cm; Longueur Tête: 185.2 cm; Hauteur Maximale: 399.1 cm; Hauteur Minimale: 399.1 cm; Surface en Plan: 4800 cm2; Surface Pied: 4800 cm2; Surface Tête: 4800 cm2; Surface de la Paroi: 73900 cm2; Volume: 1920000 cm3
IFC_Pset_Matériaux - Face gauche: Ivoire clair; Face droite: Ivoire clair; Face latérale: Ivoire clair
Pset_WallCommon - Reference: default [259,08] (..\VERTICALES\Default\)
BaseQuantities - GrossVolume: 1914873 cm3; NetVolume: 1914873 cm3; NominalLength: 185.192 cm; NominalWidth: 25.9084 cm; NominalHeight: 399.097 cm; GrossFootprintArea: 4798.01 cm2; NetFootprintArea: 4798.01 cm2; GrossSideArea: 73909.4 cm2; NetSideArea: 73909.4 cm2

# IfcWallStandardCase: default 260 (46)
Type - Material: <aucun> 26 cm
Description: Enveloppe; Group: ...de stratigraphies = default; ...de matériaux et couleurs = Ivoire clair; ...de matériaux et couleurs - 1 = Ivoire clair; ...de matériaux et couleurs - 2 = Ivoire clair
__RECOGNIZE__ - TPLG: 366; TPLG_OD: 9000; GENERATE: 1
CTLG_EXTERNAL_LINK - 0, DocType: 2; 0, Tag: 0; 0, Crc: 1977773087; 1, DocType: 2; 1, Tag: 100; 1, Crc: 1977773087; 2, DocType: 2; 2, Tag: 200; 2, Crc: 1977773087; 3, DocType: 9; 3, Tag: 0; 3, Crc: 2069987382
IFC_PSET_PolygonOffset - polygonOffsetFactor: 2; polygonOffsetUnits: 2
IFC_Pset_Caractéristiques - Stratigraphie: default [260,00]; Épaisseur: 26 cm
IFC_Pset_Caractéristiques_FRUIT - Fruit: no; Taille: 0 cm
IFC_Pset_Système de Référence Altimétrique_SUPÉRIEUR - sous Niveau: <aucun>
IFC_Pset_Système de Référence Altimétrique_INFÉRIEUR - sous Niveau: <aucun>
IFC_Pset_Matériaux - Face gauche: Ivoire clair; Face droite: Ivoire clair; Face latérale: Ivoire clair
Pset_WallCommon - Reference: default [260,00] (..\VERTICALES\Default\)
Name | In | __RECOGNIZE__, ID = IFC_Pset_Caractéristiques, ID | Alignment | ExternalFace | Numérotation | Numéro niveau | Titre niveau | Épaisseur VARIABLE | Forme en Élévation | Longueur (cm) = NominalLength (cm) | IFC_Pset_Géométrie, Hauteur (cm) = IFC_Pset_Géométrie_P1 (POINT initial), Hauteur (cm) | IFC_Pset_Géométrie, Cote (cm) = IFC_Pset_Géométrie_P1 (POINT initial), Cote (cm) = IFC_Pset_Géométrie_P2 (POINT final), Cote (cm) = IFC_Pset_Système de Référence Altimétrique_INFÉRIEUR, delta (cm) = IFC_Pset_Système de Référence Altimétrique_INFÉRIEUR, delta (P1) (cm) = IFC_Pset_Système de Référence Altimétrique_INFÉRIEUR, delta (P2) (cm) | IFC_Pset_Géométrie_P1 (POINT initial), Angle XY (deg) | IFC_Pset_Géométrie_P2 (POINT final), Hauteur (cm) | IFC_Pset_Géométrie_P2 (POINT final), Angle XY (deg) | IFC_Pset_Système de Référence Altimétrique_SUPÉRIEUR, NIVEAU | IFC_Pset_Système de Référence Altimétrique_SUPÉRIEUR, delta (cm) = IFC_Pset_Système de Référence Altimétrique_SUPÉRIEUR, delta (P1) (cm) = IFC_Pset_Système de Référence Altimétrique_SUPÉRIEUR, delta (P2) (cm) | IFC_Pset_Système de Référence Altimétrique_INFÉRIEUR, NIVEAU | Longueur Pied (cm) | Longueur Tête (cm) | Hauteur Maximale (cm) | Hauteur Minimale (cm) | Surface en Plan (cm2) = Surface Pied (cm2) | Surface Tête (cm2) | Surface de la Paroi (cm2) | Volume (cm3) | GrossVolume (cm3) | NetVolume (cm3) | NominalWidth (cm) | NominalHeight (cm) | GrossFootprintArea (cm2) = NetFootprintArea (cm2) | GrossSideArea (cm2) | NetSideArea (cm2)
Enveloppe 982657 | Default Site | 982657 | 0 | 0 | 1147 | 06 | Mezzanine | no | trapèze | 172.691 | 77 | 12.5 | 89.9479 | 77 | 269.948 | HAUT Mezzanine (Couverture 2134) | 0 | Mezzanine (Mezzanine 49003) | 172.7 | 172.7 | 77 | 77 | 4500 | 5100 | 15900 | 410000 | 414061 | 363074 | 26 | 92.2189 | 4489.98 | 15925.4 | 13964.4
Enveloppe 57016 | Rez-de-Jardin | 57016 | 0 | 1 | 0108 | 02 | Rez-de-Jardin | no | rectangle | 481.26 | 291.413 | -1.94511e-11 | 90.1418 | 291.413 | 270.142 | HAUT Rez-de-Jardin (Rez-de-chaussée 1047) | 0.0128504 | Rez-de-Jardin (Rez-de-Jardin 15545) | 481.3 | 481.3 | 291.4 | 291.4 | 12500 | 12500 | 140300 | 3650000 | 3646385 | 3646385 | 26 | 291.413 | 12512.8 | 140246 | 140246
Enveloppe 531109 | Rez-de-chaussée | 531109 | 1 | 1 | 0844 | 03 | Rez-de-chaussée | no | rectangle | 161.342 | 370.795 | 100 | 15.0092 | 370.795 | 195.009 | HAUT Rez-de-chaussée (Niveau 1 2343) | -7 | Rez-de-chaussée (Rez-de-chaussée 1047) | 161.3 | 161.3 | 370.8 | 370.8 | 4200 | 4200 | 59800 | 1550000 | 1555442 | 158547 | 26 | 370.795 | 4194.88 | 59824.7 | 6097.96
Enveloppe 531149 | Rez-de-chaussée | 531149 | 1 | 1 | 0845 | 03 | Rez-de-chaussée | no | rectangle | 172.286 | 370.795 | 100 | 0.194425 | 370.795 | 180.194 | HAUT Rez-de-chaussée (Niveau 1 2343) | -7 | Rez-de-chaussée (Rez-de-chaussée 1047) | 172.3 | 172.3 | 370.8 | 370.8 | 4500 | 4500 | 63900 | 1660000 | 1660950 | 172887 | 26 | 370.795 | 4479.43 | 63882.7 | 6649.5
Enveloppe 531070 | Rez-de-chaussée | 531070 | 1 | 1 | 0843 | 03 | Rez-de-chaussée | no | rectangle | 162.152 | 370.795 | 100 | 45.1068 | 370.795 | 225.107 | HAUT Rez-de-chaussée (Niveau 1 2343) | -7 | Rez-de-chaussée (Rez-de-chaussée 1047) | 162.2 | 162.2 | 370.8 | 370.8 | 4200 | 4200 | 60100 | 1560000 | 1563252 | 165945 | 26 | 370.795 | 4215.94 | 60125.1 | 6382.49
Enveloppe 531153 | Rez-de-chaussée | 531153 | 1 | 1 | 0846 | 03 | Rez-de-chaussée | no | rectangle | 181.901 | 370.795 | 100 | 1.21405 | 370.795 | 181.214 | HAUT Rez-de-chaussée (Niveau 1 2343) | -7 | Rez-de-chaussée (Rez-de-chaussée 1047) | 181.9 | 181.9 | 370.8 | 370.8 | 4700 | 4700 | 67400 | 1750000 | 1753648 | 192824 | 26 | 370.795 | 4729.42 | 67448 | 7416.32
Enveloppe 531203 | Rez-de-chaussée | 531203 | 1 | 1 | 0847 | 03 | Rez-de-chaussée | no | rectangle | 161.492 | 370.795 | 100 | 164.52 | 370.795 | 344.52 | HAUT Rez-de-chaussée (Niveau 1 2343) | -7 | Rez-de-chaussée (Rez-de-chaussée 1047) | 161.5 | 161.5 | 370.8 | 370.8 | 4200 | 4200 | 59900 | 1560000 | 1556897 | 158701 | 26 | 370.795 | 4198.8 | 59880.6 | 6103.89
Enveloppe 531206 | Rez-de-chaussée | 531206 | 1 | 1 | 0848 | 03 | Rez-de-chaussée | no | rectangle | 172.862 | 370.795 | 100 | 179.435 | 370.795 | 359.435 | HAUT Rez-de-chaussée (Niveau 1 2343) | -7 | Rez-de-chaussée (Rez-de-chaussée 1047) | 172.9 | 172.9 | 370.8 | 370.8 | 4500 | 4500 | 64100 | 1670000 | 1666506 | 178156 | 26 | 370.795 | 4494.41 | 64096.4 | 6852.15
Enveloppe 2023464 | Rez-de-chaussée | 2023464 | 1 | 1 | 1175 | 03 | Rez-de-chaussée | no | rectangle | 48.1175 | 968.91 | 100 | 179.435 | 968.91 | 359.435 | HAUT Niveau 2 (Mezzanine 49003) | -20 | Rez-de-chaussée (Rez-de-chaussée 1047) | 48.1 | 48.1 | 968.9 | 968.9 | 1300 | 1300 | 46600 | 1210000 | 1212160 | 1212160 | 26 | 968.91 | 1251.06 | 46621.6 | 46621.6
Enveloppe 532492 | Niveau 1 | 532492 | 1 | 1 | 0854 | 04 | Niveau 1 | no | rectangle | 154.98 | 383.115 | -7 | 106.049 | 383.115 | 286.049 | HAUT Niveau 1 (Niveau 2 13545) | 7.10543e-12 | Niveau 1 (Niveau 1 2343) | 155 | 155 | 383.1 | 383.1 | 4000 | 4000 | 59400 | 1540000 | 1543756 | 111202 | 26 | 383.115 | 4029.48 | 59375.2 | 4277
Enveloppe 532497 | Niveau 1 | 532497 | 1 | 1 | 0855 | 04 | Niveau 1 | no | rectangle | 161.533 | 383.115 | -7 | 135.823 | 383.115 | 315.823 | HAUT Niveau 1 (Niveau 2 13545) | 7.10543e-12 | Niveau 1 (Niveau 1 2343) | 161.5 | 161.5 | 383.1 | 383.1 | 4200 | 4200 | 61900 | 1610000 | 1609033 | 104720 | 26 | 383.115 | 4199.87 | 61885.9 | 4027.68
Enveloppe 532438 | Niveau 1 | 532438 | 1 | 1 | 0852 | 04 | Niveau 1 | no | rectangle | 162.02 | 383.115 | -7 | 45.1068 | 383.115 | 225.107 | HAUT Niveau 1 (Niveau 2 13545) | 7.10543e-12 | Niveau 1 (Niveau 1 2343) | 162 | 162 | 383.1 | 383.1 | 4200 | 4200 | 62100 | 1610000 | 1613881 | 100026 | 26 | 383.115 | 4212.52 | 62072.3 | 3847.16
Enveloppe 532443 | Niveau 1 | 532443 | 1 | 1 | 0853 | 04 | Niveau 1 | yes | rectangle | 156.461 | 383.115 | -7 | 73.3938 | 383.115 | 253.394 | HAUT Niveau 1 (Niveau 2 13545) | 7.10543e-12 | Niveau 1 (Niveau 1 2343) | 156.5 | 156.5 | 383.1 | 383.1 | 4200 | 4200 | 60000 | 1620000 | 1612655 | 112266 | 26.9033 | 383.115 | 4209.32 | 59942.5 | 4167.3
Enveloppe 532502 | Niveau 1 | 532502 | 1 | 1 | 0856 | 04 | Niveau 1 | no | rectangle | 161.188 | 383.115 | -7 | 164.52 | 383.115 | 344.52 | HAUT Niveau 1 (Niveau 2 13545) | 7.4607e-12 | Niveau 1 (Niveau 1 2343) | 161.2 | 161.2 | 383.1 | 383.1 | 4200 | 4200 | 61800 | 1610000 | 1605591 | 110103 | 26 | 383.115 | 4190.88 | 61753.5 | 4234.72
Enveloppe 2049972 | Niveau 1 | 2049972 | 1 | 1 | 1180 | 04 | Niveau 1 | no | rectangle | 20 | 376.102 | 101.671 | 0 | 376.102 | 180 | HAUT Niveau 2 (Mezzanine 49003) | -133.341 | Niveau 1 (Niveau 1 2343) | 20 | 20 | 376.1 | 376.1 | 500 | 500 | 7500 | 200000 | 195573 | 195573 | 26 | 376.102 | 520 | 7522.04 | 7522.04
Enveloppe 774655 | Niveau 1 | 774655 | 1 | 1 | 1113 | 04 | Niveau 1 | no | rectangle | 171.958 | 383.115 | -7 | 179.435 | 383.115 | 359.435 | HAUT Niveau 1 (Niveau 2 13545) | 7.4607e-12 | Niveau 1 (Niveau 1 2343) | 172 | 172 | 383.1 | 383.1 | 4500 | 4500 | 65900 | 1710000 | 1712876 | 103345 | 26 | 383.115 | 4470.92 | 65879.9 | 3974.82
Enveloppe 537538 | Niveau 2 | 537538 | 1 | 1 | 0863 | 05 | Niveau 2 | no | rectangle | 155.464 | 245 | 7.81597e-12 | 106.049 | 245 | 286.049 | HAUT Niveau 2 (Mezzanine 49003) | 10 | Niveau 2 (Niveau 2 13545) | 155.5 | 155.5 | 245 | 245 | 4000 | 4000 | 38100 | 990000 | 990307 | 120964 | 26 | 245 | 4042.07 | 38088.7 | 4652.48
Enveloppe 537543 | Niveau 2 | 537543 | 1 | 1 | 0864 | 05 | Niveau 2 | no | rectangle | 161.877 | 245 | 7.81597e-12 | 135.823 | 245 | 315.823 | HAUT Niveau 2 (Mezzanine 49003) | 10 | Niveau 2 (Niveau 2 13545) | 161.9 | 161.9 | 245 | 245 | 4200 | 4200 | 39700 | 1030000 | 1031154 | 114695 | 26 | 245 | 4208.79 | 39659.8 | 4411.33
Enveloppe 537528 | Niveau 2 | 537528 | 1 | 1 | 0861 | 05 | Niveau 2 | no | rectangle | 161.855 | 245 | 7.81597e-12 | 45.1068 | 245 | 225.107 | HAUT Niveau 2 (Mezzanine 49003) | 10 | Niveau 2 (Niveau 2 13545) | 161.9 | 161.9 | 245 | 245 | 4200 | 4200 | 39700 | 1030000 | 1031015 | 129665 | 26 | 245 | 4208.23 | 39654.4 | 4987.12
Enveloppe 537533 | Niveau 2 | 537533 | 1 | 1 | 0862 | 05 | Niveau 2 | no | rectangle | 156.461 | 245 | 7.81597e-12 | 73.3938 | 245 | 253.394 | HAUT Niveau 2 (Mezzanine 49003) | 10 | Niveau 2 (Niveau 2 13545) | 156.5 | 156.5 | 245 | 245 | 4100 | 4100 | 38300 | 1000000 | 996656 | 115504 | 26 | 245 | 4067.99 | 38332.9 | 4442.45
Enveloppe 537548 | Niveau 2 | 537548 | 1 | 1 | 0865 | 05 | Niveau 2 | no | rectangle | 161.188 | 245 | 7.81597e-12 | 164.52 | 245 | 344.52 | HAUT Niveau 2 (Mezzanine 49003) | 10 | Niveau 2 (Niveau 2 13545) | 161.2 | 161.2 | 245 | 245 | 4200 | 4200 | 39500 | 1030000 | 1026767 | 124138 | 26 | 245 | 4190.88 | 39491 | 4774.55
Enveloppe 537553 | Niveau 2 | 537553 | 1 | 1 | 0866 | 05 | Niveau 2 | no | rectangle | 190.2 | 245 | 7.81597e-12 | 179.435 | 245 | 359.435 | HAUT Niveau 2 (Mezzanine 49003) | 10 | Niveau 2 (Niveau 2 13545) | 190.2 | 190.2 | 245 | 245 | 4900 | 4900 | 46600 | 1210000 | 1211572 | 241234 | 26 | 245 | 4945.19 | 46598.9 | 9278.23
Enveloppe 539435 | Niveau 2 | 539435 | 1 | 1 | 0867 | 05 | Niveau 2 | no | rectangle | 180.515 | 245 | 7.4607e-12 | 0.302116 | 245 | 180.302 | HAUT Niveau 2 (Mezzanine 49003) | 10 | Niveau 2 (Niveau 2 13545) | 180.5 | 180.5 | 245 | 245 | 4700 | 4700 | 44200 | 1150000 | 1149881 | 139374 | 26 | 245 | 4693.39 | 44226.2 | 5360.54
Enveloppe 537518 | Niveau 2 | 537518 | 1 | 1 | 0859 | 05 | Niveau 2 | no | rectangle | 172.084 | 245 | 7.4607e-12 | 0.194425 | 245 | 180.194 | HAUT Niveau 2 (Mezzanine 49003) | 10 | Niveau 2 (Niveau 2 13545) | 172.1 | 172.1 | 245 | 245 | 4500 | 4500 | 42200 | 1100000 | 1096173 | 120758 | 26 | 245 | 4474.17 | 42160.5 | 4644.54
Enveloppe 537523 | Niveau 2 | 537523 | 1 | 1 | 0860 | 05 | Niveau 2 | no | rectangle | 161.242 | 245 | 7.4607e-12 | 15.0092 | 245 | 195.009 | HAUT Niveau 2 (Mezzanine 49003) | 10 | Niveau 2 (Niveau 2 13545) | 161.2 | 161.2 | 245 | 245 | 4200 | 4200 | 39500 | 1030000 | 1027110 | 118983 | 26 | 245 | 4192.28 | 39504.2 | 4576.28
Enveloppe 564896 | Mezzanine | 564896 | 1 | 1 | 0877 | 06 | Mezzanine | no | rectangle | 20.6359 | 129.891 | 10 | 0.302116 | 129.891 | 180.302 | Couverture (Couverture 2134) | -139.811 | Mezzanine (Mezzanine 49003) | 20.6 | 20.6 | 129.9 | 129.9 | 500 | 500 | 2700 | 70000 | 69691 | 69691 | 26 | 129.891 | 536.533 | 2680.42 | 2680.42
Enveloppe 1182020 | Mezzanine | 1182020 | 1 | 0 | 1159 | 06 | Mezzanine | no | trapèze | 307.709 | 68.9914 | 20.5086 | 0.267953 | 68.9914 | 180.268 | HAUT Mezzanine (Couverture 2134) | 0 | Mezzanine (Mezzanine 49003) | 307.7 | 307.7 | 69 | 69 | 8000 | 9700 | 33000 | 860000 | 857390 | 806404 | 26 | 107.168 | 8000.44 | 32976.5 | 31015.5
Enveloppe 1149553 | Mezzanine | 1149553 | 0 | 0 | 1157 | 06 | Mezzanine | no | trapèze | 298.715 | 81.1126 | 5 | 0.0433781 | 79.812 | 180.043 | HAUT Mezzanine (Couverture 2134) | 0 | Mezzanine (Mezzanine 49003) | 298.7 | 298.7 | 81.1 | 79.8 | 7800 | 10100 | 37100 | 960000 | 963701 | 963701 | 26 | 124.083 | 7766.59 | 37065.4 | 37065.4
Enveloppe 1152838 | Mezzanine | 1152838 | 1 | 0 | 1158 | 06 | Mezzanine | no | trapèze | 302.812 | 69.5 | 20 | 89.9289 | 75.3149 | 269.929 | HAUT Mezzanine (Couverture 2134) | 0 | Mezzanine (Mezzanine 49003) | 302.8 | 302.9 | 75.3 | 69.5 | 7900 | 9500 | 34000 | 880000 | 884379 | 784454 | 26 | 112.329 | 7873.12 | 34014.6 | 30171.3
Enveloppe 1003434 | Mezzanine | 1003434 | 1 | 0 | 1148 | 06 | Mezzanine | no | trapèze | 171.71 | 66.8835 | 20 | 179.953 | 66.8835 | 359.953 | HAUT Mezzanine (Couverture 2134) | 0 | Mezzanine (Mezzanine 49003) | 171.7 | 171.7 | 66.9 | 66.9 | 4500 | 5100 | 14100 | 370000 | 366897 | 315911 | 26 | 82.1818 | 4464.46 | 14111.4 | 12150.4
Enveloppe 1005744 | Mezzanine | 1005744 | 1 | 0 | 1149 | 06 | Mezzanine | no | trapèze | 171.71 | 89.5 | 1.61648e-11 | 90.0434 | 89.5 | 270.043 | HAUT Mezzanine (Couverture 2134) | -100 | Mezzanine (Mezzanine 49003) | 171.7 | 171.7 | 89.5 | 89.5 | 4500 | 5100 | 17900 | 460000 | 464774 | 391354 | 26 | 104.105 | 4464.46 | 17875.9 | 15052.1
Enveloppe 1018898 | Mezzanine | 1018898 | 1 | 0 | 1155 | 06 | Mezzanine | no | trapèze | 303.546 | 82.4887 | 10 | 179.953 | 81.4176 | 359.953 | HAUT Mezzanine (Couverture 2134) | 0 | Mezzanine (Mezzanine 49003) | 303.5 | 303.5 | 82.5 | 81.4 | 7900 | 9400 | 36300 | 940000 | 942860 | 869440 | 26 | 119.467 | 7892.21 | 36263.9 | 33440
Enveloppe 1035273 | Mezzanine | 1035273 | 1 | 0 | 1156 | 06 | Mezzanine | no | trapèze | 171.716 | 63.6428 | 30.0616 | 45.5479 | 64.3741 | 225.548 | Couverture (Couverture 2134) | 0 | Mezzanine (Mezzanine 49003) | 171.7 | 171.7 | 64.4 | 63.6 | 4500 | 5100 | 13600 | 350000 | 353193 | 302207 | 26 | 79.1094 | 4464.61 | 13584.4 | 11623.3
Enveloppe 1012987 | Mezzanine | 1012987 | 0 | 0 | 1153 | 06 | Mezzanine | no | trapèze | 171.708 | 59.4383 | 30.0616 | 135.126 | 59.4383 | 315.126 | HAUT Mezzanine (Couverture 2134) | 0 | Mezzanine (Mezzanine 49003) | 171.7 | 171.7 | 59.4 | 59.4 | 4500 | 5100 | 12800 | 330000 | 333655 | 282669 | 26 | 74.7368 | 4464.4 | 12832.9 | 10871.9
Enveloppe 1015988 | Mezzanine | 1015988 | 1 | 0 | 1154 | 06 | Mezzanine | no | trapèze | 298.715 | 84.812 | 1.59872e-11 | 0.0433781 | 86.1126 | 180.043 | HAUT Mezzanine (Couverture 2134) | 0 | Mezzanine (Mezzanine 49003) | 298.7 | 298.7 | 86.1 | 84.8 | 7800 | 10100 | 38600 | 1000000 | 1002534 | 1002534 | 26 | 129.083 | 7766.59 | 38559 | 38559
Enveloppe 551121 | Couverture | 551121 | 1 | 1 | 0869 | 07 | Couverture | no | rectangle | 161.188 | 26.5 | -165 | 164.52 | 26.5 | 344.52 | (Couverture 2134 <aucun>) | -138.5 | Couverture (Couverture 2134) | 161.2 | 161.2 | 26.5 | 26.5 | 4200 | 4200 | 4300 | 110000 | 111058 | 111058 | 26 | 26.5 | 4190.88 | 4271.48 | 4271.48
Enveloppe 557769 | Couverture | 557769 | 1 | 1 | 0872 | 07 | Couverture | no | rectangle | 156.461 | 26.5 | -165 | 73.3938 | 26.5 | 253.394 | (Couverture 2134 <aucun>) | -138.5 | Couverture (Couverture 2134) | 156.5 | 156.5 | 26.5 | 26.5 | 4100 | 4100 | 4100 | 110000 | 107802 | 107802 | 26 | 26.5 | 4067.99 | 4146.22 | 4146.22
Enveloppe 557780 | Couverture | 557780 | 1 | 1 | 0873 | 07 | Couverture | no | rectangle | 162.152 | 26.5 | -165 | 45.1068 | 26.5 | 225.107 | (Couverture 2134 <aucun>) | -138.5 | Couverture (Couverture 2134) | 162.2 | 162.2 | 26.5 | 26.5 | 4200 | 4200 | 4300 | 110000 | 111722 | 111722 | 26 | 26.5 | 4215.94 | 4297.02 | 4297.02
Enveloppe 557747 | Couverture | 557747 | 1 | 1 | 0870 | 07 | Couverture | no | rectangle | 161.533 | 26.5 | -165 | 135.823 | 26.5 | 315.823 | (Couverture 2134 <aucun>) | -138.5 | Couverture (Couverture 2134) | 161.5 | 161.5 | 26.5 | 26.5 | 4200 | 4200 | 4300 | 110000 | 111297 | 111297 | 26 | 26.5 | 4199.87 | 4280.64 | 4280.64
Enveloppe 557758 | Couverture | 557758 | 1 | 1 | 0871 | 07 | Couverture | no | rectangle | 155.464 | 26.5 | -165 | 106.049 | 26.5 | 286.049 | (Couverture 2134 <aucun>) | -138.5 | Couverture (Couverture 2134) | 155.5 | 155.5 | 26.5 | 26.5 | 4000 | 4000 | 4100 | 110000 | 107115 | 107115 | 26 | 26.5 | 4042.07 | 4119.8 | 4119.8
Enveloppe 557791 | Couverture | 557791 | 1 | 1 | 0874 | 07 | Couverture | no | rectangle | 161.242 | 26.5 | -165 | 15.0092 | 26.5 | 195.009 | (Couverture 2134 <aucun>) | -138.5 | Couverture (Couverture 2134) | 161.2 | 161.2 | 26.5 | 26.5 | 4200 | 4200 | 4300 | 110000 | 111096 | 111096 | 26 | 26.5 | 4192.28 | 4272.9 | 4272.9
Enveloppe 565350 | Couverture | 565350 | 1 | 1 | 0878 | 07 | Couverture | no | rectangle | 159.884 | 26.5 | -165 | 0.302116 | 26.5 | 180.302 | (Couverture 2134 <aucun>) | -138.5 | Couverture (Couverture 2134) | 159.9 | 159.9 | 26.5 | 26.5 | 4200 | 4200 | 4200 | 110000 | 110160 | 110160 | 26 | 26.5 | 4156.99 | 4236.93 | 4236.93
Enveloppe 557802 | Couverture | 557802 | 1 | 1 | 0875 | 07 | Couverture | no | rectangle | 172.016 | 26.5 | -165 | 0.194425 | 26.5 | 180.194 | (Couverture 2134 <aucun>) | -138.5 | Couverture (Couverture 2134) | 172 | 172 | 26.5 | 26.5 | 4500 | 4500 | 4600 | 120000 | 118519 | 118519 | 26 | 26.5 | 4472.42 | 4558.43 | 4558.43
Enveloppe 557824 | Couverture | 557824 | 0 | 1 | 0876 | 07 | Couverture | no | rectangle | 218.883 | 26.5 | -165 | 179.121 | 26.5 | 359.121 | (Couverture 2134 <aucun>) | -138.5 | Couverture (Couverture 2134) | 218.9 | 218.9 | 26.5 | 26.5 | 5700 | 5700 | 5800 | 150000 | 150810 | 150810 | 26 | 26.5 | 5690.95 | 5800.39 | 5800.39
Enveloppe 1007048 | Couverture | 1007048 | 1 | 1 | 1150 | 07 | Couverture | no | rectangle | 143.95 | 26.5 | -165 | 89.7122 | 26.5 | 269.712 | (Couverture 2134 <aucun>) | -138.5 | Couverture (Couverture 2134) | 144 | 144 | 26.5 | 26.5 | 3700 | 3700 | 3800 | 100000 | 99181.7 | 99181.7 | 26 | 26.5 | 3742.71 | 3814.68 | 3814.68
Enveloppe 1011544 | Couverture | 1011544 | 1 | 1 | 1152 | 07 | Couverture | no | rectangle | 137.294 | 26.5 | -165 | 89.4192 | 26.5 | 269.419 | (Couverture 2134 <aucun>) | -138.5 | Couverture (Couverture 2134) | 137.3 | 137.3 | 26.5 | 26.5 | 3600 | 3600 | 3600 | 90000 | 94595.4 | 94595.4 | 26 | 26.5 | 3569.64 | 3638.28 | 3638.28

# IfcWallStandardCase: default 265 (2)
Type - Material: <aucun> 26.5 cm
Description: Enveloppe; Group: ...de stratigraphies = default; ...de matériaux et couleurs = Ivoire clair; ...de matériaux et couleurs - 1 = Ivoire clair; ...de matériaux et couleurs - 2 = Ivoire clair
__RECOGNIZE__ - TPLG: 366; TPLG_OD: 9000; GENERATE: 1
CTLG_EXTERNAL_LINK - 0, DocType: 2; 0, Tag: 0; 0, Crc: 1977773087; 1, DocType: 2; 1, Tag: 100; 1, Crc: 1977773087; 2, DocType: 2; 2, Tag: 200; 2, Crc: 1977773087; 3, DocType: 9; 3, Tag: 0; 3, Crc: -967959560
IFC_PSET_PolygonOffset - polygonOffsetFactor: 2; polygonOffsetUnits: 2
IFC_Pset_Alignment - Alignment: 1
IFC_Pset_Strat_Detail_Align - ExternalFace: 1
IFC_Pset_Caractéristiques - Stratigraphie: default [265,00]; Épaisseur: 26.5 cm; Épaisseur VARIABLE: no
IFC_Pset_Caractéristiques_FRUIT - Fruit: no; Taille: 0 cm
IFC_Pset_Géométrie - Forme en Élévation: rectangle
IFC_Pset_Système de Référence Altimétrique_SUPÉRIEUR - sous Niveau: <aucun>
IFC_Pset_Système de Référence Altimétrique_INFÉRIEUR - sous Niveau: <aucun>
IFC_Pset_Matériaux - Face gauche: Ivoire clair; Face droite: Ivoire clair; Face latérale: Ivoire clair
Pset_WallCommon - Reference: default [265,00] (..\VERTICALES\Default\)
BaseQuantities - NominalWidth: 26.5 cm
Name | In | __RECOGNIZE__, ID = IFC_Pset_Caractéristiques, ID | Numérotation | Numéro niveau | Titre niveau | Longueur (cm) = NominalLength (cm) | IFC_Pset_Géométrie, Hauteur (cm) = IFC_Pset_Géométrie_P1 (POINT initial), Hauteur (cm) = IFC_Pset_Géométrie_P2 (POINT final), Hauteur (cm) = NominalHeight (cm) | IFC_Pset_Géométrie, Cote (cm) = IFC_Pset_Géométrie_P1 (POINT initial), Cote (cm) = IFC_Pset_Géométrie_P2 (POINT final), Cote (cm) = IFC_Pset_Système de Référence Altimétrique_INFÉRIEUR, delta (cm) = IFC_Pset_Système de Référence Altimétrique_INFÉRIEUR, delta (P1) (cm) = IFC_Pset_Système de Référence Altimétrique_INFÉRIEUR, delta (P2) (cm) | IFC_Pset_Géométrie_P1 (POINT initial), Angle XY (deg) | IFC_Pset_Géométrie_P2 (POINT final), Angle XY (deg) | IFC_Pset_Système de Référence Altimétrique_SUPÉRIEUR, NIVEAU | IFC_Pset_Système de Référence Altimétrique_SUPÉRIEUR, delta (cm) = IFC_Pset_Système de Référence Altimétrique_SUPÉRIEUR, delta (P1) (cm) = IFC_Pset_Système de Référence Altimétrique_SUPÉRIEUR, delta (P2) (cm) | IFC_Pset_Système de Référence Altimétrique_INFÉRIEUR, NIVEAU | Longueur Pied (cm) = Longueur Tête (cm) | Hauteur Maximale (cm) = Hauteur Minimale (cm) | Surface en Plan (cm2) = Surface Pied (cm2) = Surface Tête (cm2) | Surface de la Paroi (cm2) | Volume (cm3) | GrossVolume (cm3) | NetVolume (cm3) | GrossFootprintArea (cm2) = NetFootprintArea (cm2) | GrossSideArea (cm2) | NetSideArea (cm2)
Enveloppe 488241 | Rez-de-Jardin | 488241 | 0834 | 02 | Rez-de-Jardin | 21.2944 | 1414.2 | 106 | 28.7949 | 208.795 | Couverture (Couverture 2134) | -139.811 | Rez-de-Jardin (Rez-de-Jardin 15545) | 21.3 | 1414.2 | 600 | 30100 | 810000 | 798036 | 798036 | 564.301 | 30114.6 | 30114.6
Enveloppe 1519655 | Mezzanine | 1519655 | 1160 | 06 | Mezzanine | 173.196 | 104.702 | 10 | 179.435 | 359.435 | HAUT Mezzanine (Couverture 2134) | -165 | Mezzanine (Mezzanine 49003) | 173.2 | 104.7 | 4700 | 18100 | 490000 | 480552 | 15540.9 | 4589.69 | 18134 | 586.45

# IfcWallStandardCase: default 270 (2)
Type - Material: <aucun> 27 cm
Description: Enveloppe; Group: ...de stratigraphies = default; ...de matériaux et couleurs = Ivoire clair; ...de matériaux et couleurs - 1 = Ivoire clair; ...de matériaux et couleurs - 2 = Ivoire clair
__RECOGNIZE__ - TPLG: 366; TPLG_OD: 9000; GENERATE: 1
CTLG_EXTERNAL_LINK - 0, DocType: 2; 0, Tag: 0; 0, Crc: 1977773087; 1, DocType: 2; 1, Tag: 100; 1, Crc: 1977773087; 2, DocType: 2; 2, Tag: 200; 2, Crc: 1977773087; 3, DocType: 9; 3, Tag: 0; 3, Crc: -2078448551
IFC_PSET_PolygonOffset - polygonOffsetFactor: 2; polygonOffsetUnits: 2
IFC_Pset_Alignment - Alignment: 1
IFC_Pset_Caractéristiques - Stratigraphie: default [270,00]; Épaisseur: 27 cm; Épaisseur VARIABLE: no
IFC_Pset_Caractéristiques_FRUIT - Fruit: no; Taille: 0 cm
IFC_Pset_Géométrie - Forme en Élévation: rectangle
IFC_Pset_Système de Référence Altimétrique_SUPÉRIEUR - sous Niveau: <aucun>
IFC_Pset_Matériaux - Face gauche: Ivoire clair; Face droite: Ivoire clair; Face latérale: Ivoire clair
Pset_WallCommon - Reference: default [270,00] (..\VERTICALES\Default\)
BaseQuantities - NominalWidth: 27 cm
Name | In | __RECOGNIZE__, ID = IFC_Pset_Caractéristiques, ID | ExternalFace | Numérotation | Numéro niveau | Titre niveau | Longueur (cm) = NominalLength (cm) | IFC_Pset_Géométrie, Hauteur (cm) = IFC_Pset_Géométrie_P1 (POINT initial), Hauteur (cm) = IFC_Pset_Géométrie_P2 (POINT final), Hauteur (cm) = NominalHeight (cm) | IFC_Pset_Géométrie, Cote (cm) = IFC_Pset_Géométrie_P1 (POINT initial), Cote (cm) = IFC_Pset_Géométrie_P2 (POINT final), Cote (cm) = IFC_Pset_Système de Référence Altimétrique_INFÉRIEUR, delta (cm) = IFC_Pset_Système de Référence Altimétrique_INFÉRIEUR, delta (P1) (cm) = IFC_Pset_Système de Référence Altimétrique_INFÉRIEUR, delta (P2) (cm) | IFC_Pset_Géométrie_P1 (POINT initial), Angle XY (deg) | IFC_Pset_Géométrie_P2 (POINT final), Angle XY (deg) | IFC_Pset_Système de Référence Altimétrique_SUPÉRIEUR, NIVEAU | IFC_Pset_Système de Référence Altimétrique_SUPÉRIEUR, delta (cm) = IFC_Pset_Système de Référence Altimétrique_SUPÉRIEUR, delta (P1) (cm) = IFC_Pset_Système de Référence Altimétrique_SUPÉRIEUR, delta (P2) (cm) | IFC_Pset_Système de Référence Altimétrique_INFÉRIEUR, NIVEAU | sous Niveau | Longueur Pied (cm) = Longueur Tête (cm) | Hauteur Maximale (cm) = Hauteur Minimale (cm) | Surface en Plan (cm2) = Surface Pied (cm2) = Surface Tête (cm2) | Surface de la Paroi (cm2) | Volume (cm3) | GrossVolume (cm3) | NetVolume (cm3) | GrossFootprintArea (cm2) = NetFootprintArea (cm2) | GrossSideArea (cm2) | NetSideArea (cm2)
Enveloppe 777845 | Rez-de-Jardin | 777845 | 0 | 1129 | 02 | Rez-de-Jardin | 173.551 | 441.4 | 0 | 179.627 | 359.627 | HAUT Rez-de-Jardin (Rez-de-chaussée 1047) | 100 | Rez-de-Jardin (Rez-de-Jardin 15545) | extérieur | 173.6 | 441.4 | 4700 | 76600 | 2070000 | 2068343 | 451070 | 4685.87 | 76605.3 | 16706.3
Enveloppe 452557 | Rez-de-chaussée | 452557 | 1 | 0754 | 03 | Rez-de-chaussée | 156.64 | 370.795 | 100 | 73.6897 | 253.69 | HAUT Rez-de-chaussée (Niveau 1 2343) | -7 | Rez-de-chaussée (Rez-de-chaussée 1047) | <aucun> | 156.6 | 370.8 | 4200 | 58100 | 1570000 | 1568196 | 173646 | 4229.28 | 58081.3 | 6431.32

# IfcWallStandardCase: default 280 (3)
Type - Material: <aucun> 28 cm
Description: Enveloppe; Group: ...de stratigraphies = default; ...de matériaux et couleurs = Ivoire clair; ...de matériaux et couleurs - 1 = Ivoire clair; ...de matériaux et couleurs - 2 = Ivoire clair
__RECOGNIZE__ - TPLG: 366; TPLG_OD: 9000; GENERATE: 1
CTLG_EXTERNAL_LINK - 0, DocType: 2; 0, Tag: 0; 0, Crc: 1977773087; 1, DocType: 2; 1, Tag: 100; 1, Crc: 1977773087; 2, DocType: 2; 2, Tag: 200; 2, Crc: 1977773087; 3, DocType: 9; 3, Tag: 0; 3, Crc: -664322277
IFC_PSET_PolygonOffset - polygonOffsetFactor: 2; polygonOffsetUnits: 2
IFC_Pset_Alignment - Alignment: 1
IFC_Pset_Caractéristiques - Stratigraphie: default [280,00]; Épaisseur: 28 cm; Épaisseur VARIABLE: no
IFC_Pset_Caractéristiques_FRUIT - Fruit: no; Taille: 0 cm
IFC_Pset_Géométrie - Forme en Élévation: rectangle
IFC_Pset_Système de Référence Altimétrique_SUPÉRIEUR - sous Niveau: <aucun>
IFC_Pset_Système de Référence Altimétrique_INFÉRIEUR - sous Niveau: <aucun>
IFC_Pset_Matériaux - Face gauche: Ivoire clair; Face droite: Ivoire clair; Face latérale: Ivoire clair
Pset_WallCommon - Reference: default [280,00] (..\VERTICALES\Default\)
BaseQuantities - NominalWidth: 28 cm
Name | In | __RECOGNIZE__, ID = IFC_Pset_Caractéristiques, ID | ExternalFace | Numérotation | Numéro niveau | Titre niveau | Longueur (cm) = NominalLength (cm) | IFC_Pset_Géométrie, Hauteur (cm) = IFC_Pset_Géométrie_P1 (POINT initial), Hauteur (cm) = IFC_Pset_Géométrie_P2 (POINT final), Hauteur (cm) = NominalHeight (cm) | IFC_Pset_Géométrie, Cote (cm) = IFC_Pset_Géométrie_P1 (POINT initial), Cote (cm) = IFC_Pset_Géométrie_P2 (POINT final), Cote (cm) = IFC_Pset_Système de Référence Altimétrique_INFÉRIEUR, delta (cm) = IFC_Pset_Système de Référence Altimétrique_INFÉRIEUR, delta (P1) (cm) = IFC_Pset_Système de Référence Altimétrique_INFÉRIEUR, delta (P2) (cm) | IFC_Pset_Géométrie_P1 (POINT initial), Angle XY (deg) | IFC_Pset_Géométrie_P2 (POINT final), Angle XY (deg) | IFC_Pset_Système de Référence Altimétrique_SUPÉRIEUR, NIVEAU | IFC_Pset_Système de Référence Altimétrique_SUPÉRIEUR, delta (cm) = IFC_Pset_Système de Référence Altimétrique_SUPÉRIEUR, delta (P1) (cm) = IFC_Pset_Système de Référence Altimétrique_SUPÉRIEUR, delta (P2) (cm) | IFC_Pset_Système de Référence Altimétrique_INFÉRIEUR, NIVEAU | Longueur Pied (cm) = Longueur Tête (cm) | Hauteur Maximale (cm) = Hauteur Minimale (cm) | Surface en Plan (cm2) = Surface Pied (cm2) = Surface Tête (cm2) | Surface de la Paroi (cm2) | Volume (cm3) | GrossVolume (cm3) | NetVolume (cm3) | GrossFootprintArea (cm2) = NetFootprintArea (cm2) | GrossSideArea (cm2) | NetSideArea (cm2)
Enveloppe 452652 | Rez-de-chaussée | 452652 | 1 | 0755 | 03 | Rez-de-chaussée | 155.72 | 370.795 | 100 | 106.049 | 286.049 | HAUT Rez-de-chaussée (Niveau 1 2343) | -7 | Rez-de-chaussée (Rez-de-chaussée 1047) | 155.7 | 370.8 | 4400 | 57700 | 1620000 | 1616731 | 175313 | 4360.17 | 57740.4 | 6261.18
Enveloppe 179560 | Niveau 2 | 179560 | 0 | 0466 | 05 | Niveau 2 | 119.072 | 10 | 235 | 0.558822 | 180.559 | HAUT Niveau 2 (Mezzanine 49003) | 10 | Niveau 2 (Niveau 2 13545) | 119.1 | 10 | 3300 | 1200 | 30000 | 33340.1 | 33340.1 | 3334.01 | 1190.72 | 1190.72
Enveloppe 179805 | Niveau 2 | 179805 | 0 | 0467 | 05 | Niveau 2 | 116.672 | 10 | 235 | 0.558822 | 180.559 | HAUT Niveau 2 (Mezzanine 49003) | 10 | Niveau 2 (Niveau 2 13545) | 116.7 | 10 | 3300 | 1200 | 30000 | 32668.2 | 32668.2 | 3266.82 | 1166.72 | 1166.72

# IfcWallStandardCase: default 290 (2)
In: Rez-de-Jardin
Type - Material: <aucun> 29 cm
Description: Enveloppe; Group: ...de stratigraphies = default; ...de matériaux et couleurs = Ivoire clair; ...de matériaux et couleurs - 1 = Ivoire clair; ...de matériaux et couleurs - 2 = Ivoire clair
__RECOGNIZE__ - TPLG: 366; TPLG_OD: 9000; GENERATE: 1
CTLG_EXTERNAL_LINK - 0, DocType: 2; 0, Tag: 0; 0, Crc: 1977773087; 1, DocType: 2; 1, Tag: 100; 1, Crc: 1977773087; 2, DocType: 2; 2, Tag: 200; 2, Crc: 1977773087; 3, DocType: 9; 3, Tag: 0; 3, Crc: 1365445749
IFC_PSET_PolygonOffset - polygonOffsetFactor: 2; polygonOffsetUnits: 2
IFC_Pset_Strat_Detail_Align - ExternalFace: 1
IFC_Pset_Caractéristiques - Numéro niveau: 02; Titre niveau: Rez-de-Jardin; Stratigraphie: default [290,00]; Épaisseur: 29 cm
IFC_Pset_Caractéristiques_FRUIT - Fruit: no; Taille: 0 cm
IFC_Pset_Géométrie - Forme en Élévation: rectangle; Hauteur: 291.413 cm; Cote: -1.94511e-11 cm
IFC_Pset_Géométrie_P1 (POINT initial) - Hauteur: 291.413 cm; Cote: -1.94511e-11 cm
IFC_Pset_Géométrie_P2 (POINT final) - Hauteur: 291.413 cm; Cote: -1.94511e-11 cm
IFC_Pset_Système de Référence Altimétrique_SUPÉRIEUR - NIVEAU: HAUT Rez-de-Jardin (Rez-de-chaussée 1047); delta: 0.0128504 cm; delta (P1): 0.0128504 cm; delta (P2): 0.0128504 cm; sous Niveau: <aucun>
IFC_Pset_Système de Référence Altimétrique_INFÉRIEUR - NIVEAU: Rez-de-Jardin (Rez-de-Jardin 15545); delta: -1.94511e-11 cm; delta (P1): -1.94511e-11 cm; delta (P2): -1.94511e-11 cm; sous Niveau: <aucun>
IFC_Pset_Données Métré - Hauteur Maximale: 291.4 cm; Hauteur Minimale: 291.4 cm
IFC_Pset_Matériaux - Face gauche: Ivoire clair; Face droite: Ivoire clair; Face latérale: Ivoire clair
Pset_WallCommon - Reference: default [290,00] (..\VERTICALES\Default\)
BaseQuantities - NominalHeight: 291.413 cm
Name | __RECOGNIZE__, ID = IFC_Pset_Caractéristiques, ID | Alignment | Numérotation | Épaisseur VARIABLE | Longueur (cm) = NominalLength (cm) | IFC_Pset_Géométrie_P1 (POINT initial), Angle XY (deg) | IFC_Pset_Géométrie_P2 (POINT final), Angle XY (deg) | Longueur Pied (cm) = Longueur Tête (cm) | Surface en Plan (cm2) = Surface Pied (cm2) = Surface Tête (cm2) | Surface de la Paroi (cm2) | Volume (cm3) | GrossVolume (cm3) = NetVolume (cm3) | NominalWidth (cm) | GrossFootprintArea (cm2) = NetFootprintArea (cm2) | GrossSideArea (cm2) = NetSideArea (cm2)
Enveloppe 327406 | 327406 | 1 | 0559 | no | 94.3231 | 89.933 | 269.933 | 94.3 | 2700 | 27500 | 800000 | 797123 | 29 | 2735.37 | 27487
Enveloppe 328179 | 328179 | 0 | 0560 | yes | 93.1365 | 89.419 | 269.419 | 93.1 | 2800 | 27100 | 810000 | 807720 | 29.7599 | 2771.73 | 27141.2

# IfcWallStandardCase: default 30 (7)
Type - Material: <aucun> 3 cm
Description: Enveloppe; Group: ...de matériaux et couleurs = Chêne; ...de stratigraphies = default; ...de matériaux et couleurs - 1 = Chêne; ...de matériaux et couleurs - 2 = Chêne
__RECOGNIZE__ - TPLG: 366; TPLG_OD: 9000; GENERATE: 1
CTLG_EXTERNAL_LINK - 0, DocType: 2; 0, Tag: 0; 0, Crc: -1156274542; 1, DocType: 2; 1, Tag: 100; 1, Crc: -1156274542; 2, DocType: 2; 2, Tag: 200; 2, Crc: -1156274542; 3, DocType: 9; 3, Tag: 0; 3, Crc: -972403105
IFC_PSET_PolygonOffset - polygonOffsetFactor: 2; polygonOffsetUnits: 2
IFC_Pset_Strat_Detail_Align - ExternalFace: 1
IFC_Pset_Caractéristiques - Stratigraphie: default [30,00]; Épaisseur: 3 cm; Épaisseur VARIABLE: no
IFC_Pset_Caractéristiques_FRUIT - Fruit: no; Taille: 0 cm
IFC_Pset_Géométrie - Forme en Élévation: rectangle
IFC_Pset_Système de Référence Altimétrique_SUPÉRIEUR - sous Niveau: <aucun>
IFC_Pset_Système de Référence Altimétrique_INFÉRIEUR - sous Niveau: <aucun>
IFC_Pset_Données Métré - Surface en Plan: 300 cm2; Surface Pied: 300 cm2; Surface Tête: 300 cm2
IFC_Pset_Matériaux - Face gauche: Chêne; Face droite: Chêne; Face latérale: Chêne
Pset_WallCommon - Reference: default [30,00] (..\VERTICALES\Default\)
BaseQuantities - NominalWidth: 3 cm
Name | In | __RECOGNIZE__, ID = IFC_Pset_Caractéristiques, ID | Alignment | Numérotation | Numéro niveau | Titre niveau | Longueur (cm) = NominalLength (cm) | IFC_Pset_Géométrie, Hauteur (cm) = IFC_Pset_Géométrie_P1 (POINT initial), Hauteur (cm) = IFC_Pset_Géométrie_P2 (POINT final), Hauteur (cm) = NominalHeight (cm) | IFC_Pset_Géométrie, Cote (cm) = IFC_Pset_Géométrie_P1 (POINT initial), Cote (cm) = IFC_Pset_Géométrie_P2 (POINT final), Cote (cm) = IFC_Pset_Système de Référence Altimétrique_INFÉRIEUR, delta (cm) = IFC_Pset_Système de Référence Altimétrique_INFÉRIEUR, delta (P1) (cm) = IFC_Pset_Système de Référence Altimétrique_INFÉRIEUR, delta (P2) (cm) | IFC_Pset_Géométrie_P1 (POINT initial), Angle XY (deg) | IFC_Pset_Géométrie_P2 (POINT final), Angle XY (deg) | IFC_Pset_Système de Référence Altimétrique_SUPÉRIEUR, NIVEAU | IFC_Pset_Système de Référence Altimétrique_SUPÉRIEUR, delta (cm) = IFC_Pset_Système de Référence Altimétrique_SUPÉRIEUR, delta (P1) (cm) = IFC_Pset_Système de Référence Altimétrique_SUPÉRIEUR, delta (P2) (cm) | IFC_Pset_Système de Référence Altimétrique_INFÉRIEUR, NIVEAU | Longueur Pied (cm) = Longueur Tête (cm) | Hauteur Maximale (cm) = Hauteur Minimale (cm) | Surface de la Paroi (cm2) | Volume (cm3) | GrossVolume (cm3) | NetVolume (cm3) | GrossFootprintArea (cm2) = NetFootprintArea (cm2) | GrossSideArea (cm2) | NetSideArea (cm2)
Enveloppe 198751 | Niveau 2 | 198751 | 1 | 0498 | 05 | Niveau 2 | 102.288 | 235 | 1.06581e-12 | 179.652 | 359.652 | HAUT Niveau 2 (Mezzanine 49003) | 4.08562e-12 | Niveau 2 (Niveau 2 13545) | 102.3 | 235 | 24000 | 70000 | 72112.8 | 72112.8 | 306.863 | 24037.6 | 24037.6
Enveloppe 198834 | Niveau 2 | 198834 | 0 | 0499 | 05 | Niveau 2 | 102.712 | 235 | 1.06581e-12 | 89.6528 | 269.653 | HAUT Niveau 2 (Mezzanine 49003) | 4.08562e-12 | Niveau 2 (Niveau 2 13545) | 102.7 | 235 | 24100 | 70000 | 72412.3 | 72412.3 | 308.137 | 24137.4 | 24137.4
Enveloppe 198864 | Niveau 2 | 198864 | 1 | 0500 | 05 | Niveau 2 | 103.346 | 235 | 1.06581e-12 | 0.662734 | 180.663 | HAUT Niveau 2 (Mezzanine 49003) | 5.15143e-12 | Niveau 2 (Niveau 2 13545) | 103.3 | 235 | 24300 | 70000 | 72859.2 | 61021.3 | 310.039 | 24286.4 | 20340.4
Enveloppe 199234 | Mezzanine | 199234 | 0 | 0502 | 06 | Mezzanine | 102.763 | 209.709 | 2 | 89.6528 | 269.653 | HAUT Mezzanine (Couverture 2134) | -67.993 | Mezzanine (Mezzanine 49003) | 102.8 | 209.7 | 21600 | 60000 | 64651 | 64651 | 308.288 | 21550.3 | 21550.3
Enveloppe 199252 | Mezzanine | 199252 | 1 | 0503 | 06 | Mezzanine | 110.722 | 209.709 | 2 | 0.662734 | 180.663 | HAUT Mezzanine (Couverture 2134) | -67.993 | Mezzanine (Mezzanine 49003) | 110.7 | 209.7 | 23200 | 70000 | 69658.4 | 69658.4 | 332.167 | 23219.5 | 23219.5
Enveloppe 199183 | Mezzanine | 199183 | 0 | 0501 | 06 | Mezzanine | 107.347 | 209.709 | 2 | 0.118676 | 180.119 | HAUT Mezzanine (Couverture 2134) | -67.993 | Mezzanine (Mezzanine 49003) | 107.3 | 209.7 | 22500 | 70000 | 67535.1 | 67535.1 | 322.041 | 22511.7 | 22511.7
Enveloppe 199270 | Mezzanine | 199270 | 1 | 0504 | 06 | Mezzanine | 101.597 | 209.709 | 2 | 91.5468 | 271.547 | HAUT Mezzanine (Couverture 2134) | -67.993 | Mezzanine (Mezzanine 49003) | 101.6 | 209.7 | 21300 | 60000 | 63917.8 | 63917.8 | 304.792 | 21305.9 | 21305.9

# IfcWallStandardCase: default 300, Enveloppe 3097
In: Rez-de-chaussée
Type - Material: <aucun> 30 cm
Description: Enveloppe; Group: ...de stratigraphies = default; ...de matériaux et couleurs = Ivoire clair; ...de matériaux et couleurs - 1 = Ivoire clair; ...de matériaux et couleurs - 2 = Ivoire clair
__RECOGNIZE__ - ID: 3097; TPLG: 366; TPLG_OD: 9000; GENERATE: 1
CTLG_EXTERNAL_LINK - 0, DocType: 2; 0, Tag: 0; 0, Crc: 1977773087; 1, DocType: 2; 1, Tag: 100; 1, Crc: 1977773087; 2, DocType: 2; 2, Tag: 200; 2, Crc: 1977773087; 3, DocType: 9; 3, Tag: 0; 3, Crc: -428852228
IFC_PSET_PolygonOffset - polygonOffsetFactor: 2; polygonOffsetUnits: 2
IFC_Pset_Alignment - Alignment: 0
IFC_Pset_Strat_Detail_Align - ExternalFace: 0
IFC_Pset_Caractéristiques - ID: 3097; Numérotation: 0021; Numéro niveau: 03; Titre niveau: Rez-de-chaussée; Stratigraphie: default [300,00]; Épaisseur: 30 cm; Épaisseur VARIABLE: yes
IFC_Pset_Caractéristiques_FRUIT - Fruit: no; Taille: 0 cm
IFC_Pset_Géométrie - Forme en Élévation: rectangle; Longueur: 875.895 cm; Hauteur: 477.795 cm; Cote: 0.0128504 cm
IFC_Pset_Géométrie_P1 (POINT initial) - Hauteur: 477.795 cm; Cote: 0.0128504 cm; Angle XY: 1.14033 deg
IFC_Pset_Géométrie_P2 (POINT final) - Hauteur: 477.795 cm; Cote: 0.0128504 cm; Angle XY: 181.14 deg
IFC_Pset_Système de Référence Altimétrique_SUPÉRIEUR - NIVEAU: HAUT Rez-de-chaussée (Niveau 1 2343); delta: 0.0128504 cm; delta (P1): 0.0128504 cm; delta (P2): 0.0128504 cm; sous Niveau: <aucun>
IFC_Pset_Système de Référence Altimétrique_INFÉRIEUR - NIVEAU: Rez-de-chaussée (Rez-de-chaussée 1047); delta: 0.0128504 cm; delta (P1): 0.0128504 cm; delta (P2): 0.0128504 cm; sous Niveau: <aucun>
IFC_Pset_Données Métré - Longueur Pied: 875.9 cm; Longueur Tête: 875.9 cm; Hauteur Maximale: 477.8 cm; Hauteur Minimale: 477.8 cm; Surface en Plan: 32600 cm2; Surface Pied: 32600 cm2; Surface Tête: 32600 cm2; Surface de la Paroi: 418500 cm2; Volume: 15480000 cm3
IFC_Pset_Matériaux - Face gauche: Ivoire clair; Face droite: Ivoire clair; Face latérale: Ivoire clair
Pset_WallCommon - Reference: default [300,00] (..\VERTICALES\Default\)
BaseQuantities - GrossVolume: 15576562 cm3; NetVolume: 8603946 cm3; NominalLength: 875.895 cm; NominalWidth: 37.2201 cm; NominalHeight: 477.795 cm; GrossFootprintArea: 32600.9 cm2; NetFootprintArea: 32600.9 cm2; GrossSideArea: 418498 cm2; NetSideArea: 232231 cm2

# IfcWallStandardCase: default 320, Enveloppe 164229
In: Niveau 2
Type - Material: <aucun> 32 cm
Description: Enveloppe; Group: ...de stratigraphies = default; ...de matériaux et couleurs = Ivoire clair; ...de matériaux et couleurs - 1 = Ivoire clair; ...de matériaux et couleurs - 2 = Ivoire clair
__RECOGNIZE__ - ID: 164229; TPLG: 366; TPLG_OD: 9000; GENERATE: 1
CTLG_EXTERNAL_LINK - 0, DocType: 2; 0, Tag: 0; 0, Crc: 1977773087; 1, DocType: 2; 1, Tag: 100; 1, Crc: 1977773087; 2, DocType: 2; 2, Tag: 200; 2, Crc: 1977773087; 3, DocType: 9; 3, Tag: 0; 3, Crc: -2131757135
IFC_PSET_PolygonOffset - polygonOffsetFactor: 2; polygonOffsetUnits: 2
IFC_Pset_Alignment - Alignment: 1
IFC_Pset_Strat_Detail_Align - ExternalFace: 0
IFC_Pset_Caractéristiques - ID: 164229; Numérotation: 0396; Numéro niveau: 05; Titre niveau: Niveau 2; Stratigraphie: default [320,00]; Épaisseur: 32 cm; Épaisseur VARIABLE: no
IFC_Pset_Caractéristiques_FRUIT - Fruit: no; Taille: 0 cm
IFC_Pset_Géométrie - Forme en Élévation: rectangle; Longueur: 105.325 cm; Hauteur: 65 cm; Cote: 170 cm
IFC_Pset_Géométrie_P1 (POINT initial) - Hauteur: 65 cm; Cote: 170 cm; Angle XY: 0.94825 deg
IFC_Pset_Géométrie_P2 (POINT final) - Hauteur: 65 cm; Cote: 170 cm; Angle XY: 180.948 deg
IFC_Pset_Système de Référence Altimétrique_SUPÉRIEUR - NIVEAU: HAUT Niveau 2 (Mezzanine 49003); delta: 1.42109e-12 cm; delta (P1): 1.42109e-12 cm; delta (P2): 1.42109e-12 cm; sous Niveau: <aucun>
IFC_Pset_Système de Référence Altimétrique_INFÉRIEUR - NIVEAU: Niveau 2 (Niveau 2 13545); delta: 170 cm; delta (P1): 170 cm; delta (P2): 170 cm; sous Niveau: <aucun>
IFC_Pset_Données Métré - Longueur Pied: 105.3 cm; Longueur Tête: 105.3 cm; Hauteur Maximale: 65 cm; Hauteur Minimale: 65 cm; Surface en Plan: 3400 cm2; Surface Pied: 3400 cm2; Surface Tête: 3400 cm2; Surface de la Paroi: 6800 cm2; Volume: 220000 cm3
IFC_Pset_Matériaux - Face gauche: Ivoire clair; Face droite: Ivoire clair; Face latérale: Ivoire clair
Pset_WallCommon - Reference: default [320,00] (..\VERTICALES\Default\)
BaseQuantities - GrossVolume: 219076 cm3; NetVolume: 219076 cm3; NominalLength: 105.325 cm; NominalWidth: 32 cm; NominalHeight: 65 cm; GrossFootprintArea: 3370.4 cm2; NetFootprintArea: 3370.4 cm2; GrossSideArea: 6846.12 cm2; NetSideArea: 6846.12 cm2

# IfcWallStandardCase: default 330 (3)
In: Mezzanine
Type - Material: <aucun> 33 cm
Description: Enveloppe; Group: ...de stratigraphies = default; ...de matériaux et couleurs = Ivoire clair; ...de matériaux et couleurs - 1 = Ivoire clair; ...de matériaux et couleurs - 2 = Ivoire clair
__RECOGNIZE__ - TPLG: 366; TPLG_OD: 9000; GENERATE: 1
CTLG_EXTERNAL_LINK - 0, DocType: 2; 0, Tag: 0; 0, Crc: 1977773087; 1, DocType: 2; 1, Tag: 100; 1, Crc: 1977773087; 2, DocType: 2; 2, Tag: 200; 2, Crc: 1977773087; 3, DocType: 9; 3, Tag: 0; 3, Crc: 1568766495
IFC_PSET_PolygonOffset - polygonOffsetFactor: 2; polygonOffsetUnits: 2
IFC_Pset_Alignment - Alignment: 0
IFC_Pset_Strat_Detail_Align - ExternalFace: 0
IFC_Pset_Caractéristiques - Numéro niveau: 06; Titre niveau: Mezzanine; Stratigraphie: default [330,00]; Épaisseur: 33 cm; Épaisseur VARIABLE: no
IFC_Pset_Caractéristiques_FRUIT - Fruit: no; Taille: 0 cm
IFC_Pset_Système de Référence Altimétrique_SUPÉRIEUR - sous Niveau: <aucun>
IFC_Pset_Système de Référence Altimétrique_INFÉRIEUR - NIVEAU: Mezzanine (Mezzanine 49003); sous Niveau: <aucun>
IFC_Pset_Matériaux - Face gauche: Ivoire clair; Face droite: Ivoire clair; Face latérale: Ivoire clair
Pset_WallCommon - Reference: default [330,00] (..\VERTICALES\Default\)
BaseQuantities - NominalWidth: 33 cm
Name | __RECOGNIZE__, ID = IFC_Pset_Caractéristiques, ID | Numérotation | Forme en Élévation | Longueur (cm) = NominalLength (cm) | IFC_Pset_Géométrie, Hauteur (cm) = IFC_Pset_Géométrie_P1 (POINT initial), Hauteur (cm) | IFC_Pset_Géométrie, Cote (cm) = IFC_Pset_Géométrie_P1 (POINT initial), Cote (cm) = IFC_Pset_Géométrie_P2 (POINT final), Cote (cm) = IFC_Pset_Système de Référence Altimétrique_INFÉRIEUR, delta (cm) = IFC_Pset_Système de Référence Altimétrique_INFÉRIEUR, delta (P1) (cm) = IFC_Pset_Système de Référence Altimétrique_INFÉRIEUR, delta (P2) (cm) | IFC_Pset_Géométrie_P1 (POINT initial), Angle XY (deg) | IFC_Pset_Géométrie_P2 (POINT final), Hauteur (cm) | IFC_Pset_Géométrie_P2 (POINT final), Angle XY (deg) | NIVEAU | IFC_Pset_Système de Référence Altimétrique_SUPÉRIEUR, delta (cm) = IFC_Pset_Système de Référence Altimétrique_SUPÉRIEUR, delta (P1) (cm) = IFC_Pset_Système de Référence Altimétrique_SUPÉRIEUR, delta (P2) (cm) | Longueur Pied (cm) = Longueur Tête (cm) | Hauteur Maximale (cm) = Hauteur Minimale (cm) | Surface en Plan (cm2) = Surface Pied (cm2) | Surface Tête (cm2) | Surface de la Paroi (cm2) | Volume (cm3) | GrossVolume (cm3) | NetVolume (cm3) | NominalHeight (cm) | GrossFootprintArea (cm2) = NetFootprintArea (cm2) | GrossSideArea (cm2) | NetSideArea (cm2)
Enveloppe 783922 | 783922 | 1141 | rectangle | 619.32 | 45 | 30.0616 | 90.2887 | 45 | 270.289 | (Mezzanine 49003 <aucun>) | 75.0616 | 619.3 | 45 | 20400 | 20400 | 27900 | 920000 | 919691 | 919691 | 45 | 20437.6 | 27869.4 | 27869.4
Enveloppe 965017 | 965017 | 1145 | trapèze | 500.153 | 4.33837 | 75.0616 | 89.8054 | 4.3 | 269.805 | HAUT Mezzanine (Couverture 2134) | 0 | 500.2 | 4.3 | 16500 | 19200 | 40400 | 1330000 | 1333019 | 1333019 | 80.7643 | 16505 | 40394.5 | 40394.5
Enveloppe 969142 | 969142 | 1146 | trapèze | 330.392 | 52.3918 | 165 | 89.8054 | 52.3918 | 269.805 | HAUT Mezzanine (Couverture 2134) | 0 | 330.4 | 52.4 | 10900 | 18100 | 40300 | 1330000 | 1329597 | 1226862 | 121.948 | 10902.9 | 40290.8 | 37177.6

# IfcWallStandardCase: default 340, Enveloppe 166728
In: Niveau 2
Type - Material: <aucun> 34 cm
Description: Enveloppe; Group: ...de stratigraphies = default; ...de matériaux et couleurs = Ivoire clair; ...de matériaux et couleurs - 1 = Ivoire clair; ...de matériaux et couleurs - 2 = Ivoire clair
__RECOGNIZE__ - ID: 166728; TPLG: 366; TPLG_OD: 9000; GENERATE: 1
CTLG_EXTERNAL_LINK - 0, DocType: 2; 0, Tag: 0; 0, Crc: 1977773087; 1, DocType: 2; 1, Tag: 100; 1, Crc: 1977773087; 2, DocType: 2; 2, Tag: 200; 2, Crc: 1977773087; 3, DocType: 9; 3, Tag: 0; 3, Crc: 167612473
IFC_PSET_PolygonOffset - polygonOffsetFactor: 2; polygonOffsetUnits: 2
IFC_Pset_Alignment - Alignment: 1
IFC_Pset_Strat_Detail_Align - ExternalFace: 0
IFC_Pset_Caractéristiques - ID: 166728; Numérotation: 0402; Numéro niveau: 05; Titre niveau: Niveau 2; Stratigraphie: default [340,00]; Épaisseur: 34 cm; Épaisseur VARIABLE: no
IFC_Pset_Caractéristiques_FRUIT - Fruit: no; Taille: 0 cm
IFC_Pset_Géométrie - Forme en Élévation: rectangle; Longueur: 74.604 cm; Hauteur: 10 cm; Cote: 230 cm
IFC_Pset_Géométrie_P1 (POINT initial) - Hauteur: 10 cm; Cote: 230 cm; Angle XY: 2.11917 deg
IFC_Pset_Géométrie_P2 (POINT final) - Hauteur: 10 cm; Cote: 230 cm; Angle XY: 182.119 deg
IFC_Pset_Système de Référence Altimétrique_SUPÉRIEUR - NIVEAU: HAUT Niveau 2 (Mezzanine 49003); delta: 5 cm; delta (P1): 5 cm; delta (P2): 5 cm; sous Niveau: <aucun>
IFC_Pset_Système de Référence Altimétrique_INFÉRIEUR - NIVEAU: Niveau 2 (Niveau 2 13545); delta: 230 cm; delta (P1): 230 cm; delta (P2): 230 cm; sous Niveau: <aucun>
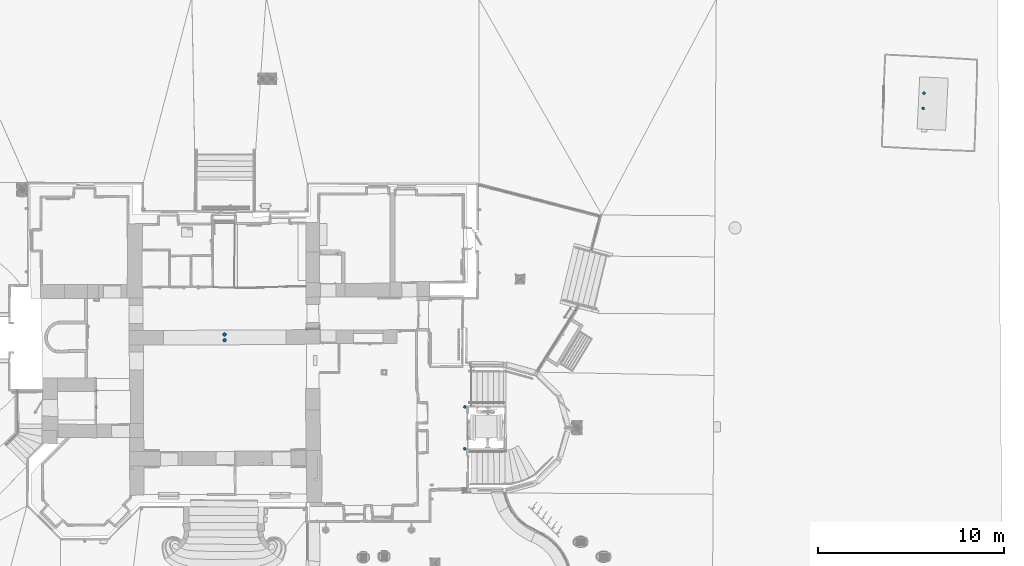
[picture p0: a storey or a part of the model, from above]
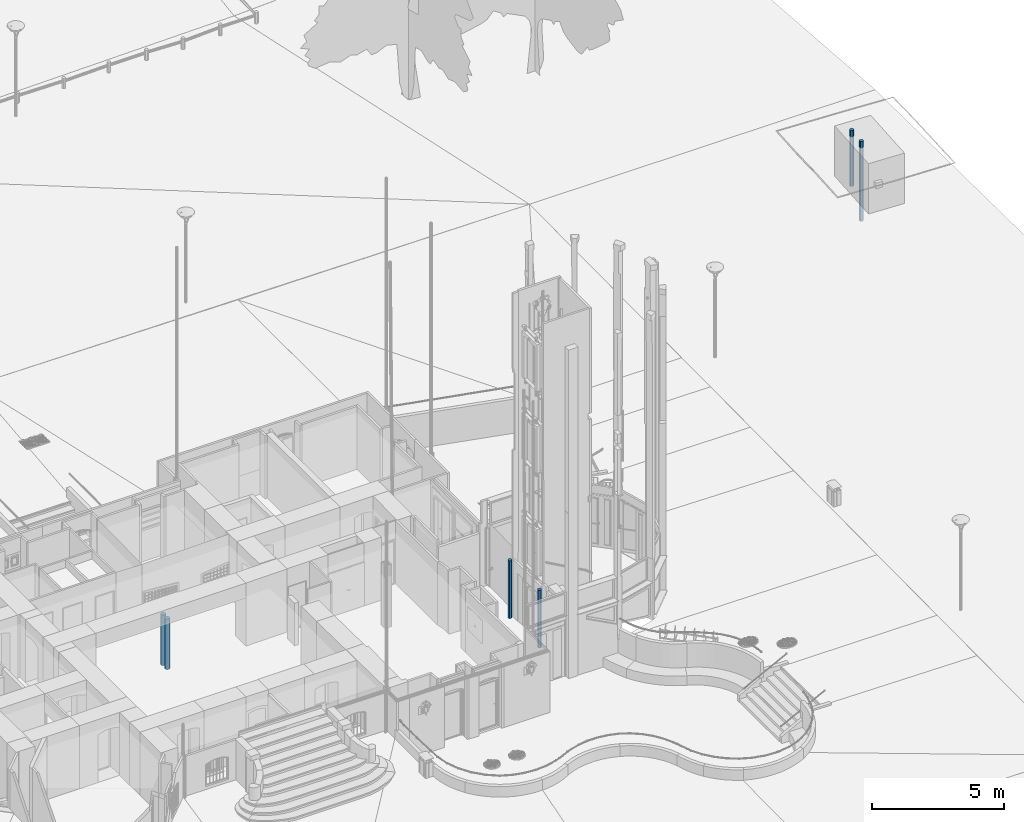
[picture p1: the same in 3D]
Properties of the parts of a building model (IFC2X3), part 24 of 37

# IfcWallStandardCase: default 340, Enveloppe 166728
IFC_Pset_Données Métré - Longueur Pied: 74.6 cm; Longueur Tête: 74.6 cm; Hauteur Maximale: 10 cm; Hauteur Minimale: 10 cm; Surface en Plan: 2500 cm2; Surface Pied: 2500 cm2; Surface Tête: 2500 cm2; Surface de la Paroi: 700 cm2; Volume: 20000 cm3
IFC_Pset_Matériaux - Face gauche: Ivoire clair; Face droite: Ivoire clair; Face latérale: Ivoire clair
Pset_WallCommon - Reference: default [340,00] (..\VERTICALES\Default\)
BaseQuantities - GrossVolume: 25365.4 cm3; NetVolume: 25365.4 cm3; NominalLength: 74.604 cm; NominalWidth: 34 cm; NominalHeight: 10 cm; GrossFootprintArea: 2536.54 cm2; NetFootprintArea: 2536.54 cm2; GrossSideArea: 746.04 cm2; NetSideArea: 746.04 cm2

# IfcWallStandardCase: default 350 (3)
In: Niveau 2
Type - Material: <aucun> 35 cm
Description: Enveloppe; Group: ...de stratigraphies = default; ...de matériaux et couleurs = Ivoire clair; ...de matériaux et couleurs - 1 = Ivoire clair; ...de matériaux et couleurs - 2 = Ivoire clair
__RECOGNIZE__ - TPLG: 366; TPLG_OD: 9000; GENERATE: 1
CTLG_EXTERNAL_LINK - 0, DocType: 2; 0, Tag: 0; 0, Crc: 1977773087; 1, DocType: 2; 1, Tag: 100; 1, Crc: 1977773087; 2, DocType: 2; 2, Tag: 200; 2, Crc: 1977773087; 3, DocType: 9; 3, Tag: 0; 3, Crc: 1651836767
IFC_PSET_PolygonOffset - polygonOffsetFactor: 2; polygonOffsetUnits: 2
IFC_Pset_Strat_Detail_Align - ExternalFace: 0
IFC_Pset_Caractéristiques - Numéro niveau: 05; Titre niveau: Niveau 2; Stratigraphie: default [350,00]; Épaisseur: 35 cm
IFC_Pset_Caractéristiques_FRUIT - Fruit: no; Taille: 0 cm
IFC_Pset_Géométrie - Forme en Élévation: rectangle
IFC_Pset_Système de Référence Altimétrique_SUPÉRIEUR - NIVEAU: HAUT Niveau 2 (Mezzanine 49003); delta: 5 cm; delta (P1): 5 cm; delta (P2): 5 cm; sous Niveau: <aucun>
IFC_Pset_Système de Référence Altimétrique_INFÉRIEUR - NIVEAU: Niveau 2 (Niveau 2 13545); sous Niveau: <aucun>
IFC_Pset_Matériaux - Face gauche: Ivoire clair; Face droite: Ivoire clair; Face latérale: Ivoire clair
Pset_WallCommon - Reference: default [350,00] (..\VERTICALES\Default\)
Name | __RECOGNIZE__, ID = IFC_Pset_Caractéristiques, ID | Alignment | Numérotation | Épaisseur VARIABLE | Longueur (cm) = NominalLength (cm) | IFC_Pset_Géométrie, Hauteur (cm) = IFC_Pset_Géométrie_P1 (POINT initial), Hauteur (cm) = IFC_Pset_Géométrie_P2 (POINT final), Hauteur (cm) = Hauteur Maximale (cm) = Hauteur Minimale (cm) = NominalHeight (cm) | IFC_Pset_Géométrie, Cote (cm) = IFC_Pset_Géométrie_P1 (POINT initial), Cote (cm) = IFC_Pset_Géométrie_P2 (POINT final), Cote (cm) = delta (cm) = delta (P1) (cm) = delta (P2) (cm) | IFC_Pset_Géométrie_P1 (POINT initial), Angle XY (deg) | IFC_Pset_Géométrie_P2 (POINT final), Angle XY (deg) | Longueur Pied (cm) = Longueur Tête (cm) | Surface en Plan (cm2) = Surface Pied (cm2) = Surface Tête (cm2) | Surface de la Paroi (cm2) | Volume (cm3) | GrossVolume (cm3) = NetVolume (cm3) | NominalWidth (cm) | GrossFootprintArea (cm2) = NetFootprintArea (cm2) | GrossSideArea (cm2) = NetSideArea (cm2)
Enveloppe 150780 | 150780 | 1 | 0340 | no | 206.976 | 240 | 1.42109e-12 | 89.8686 | 269.869 | 207 | 7200 | 49700 | 1740000 | 1738597 | 35 | 7244.15 | 49674.2
Enveloppe 152957 | 152957 | 1 | 0356 | no | 76.2633 | 240 | 1.42109e-12 | 89.6756 | 269.676 | 76.3 | 2700 | 18300 | 640000 | 640611 | 35 | 2669.21 | 18303.2
Enveloppe 166404 | 166404 | 0 | 0399 | yes | 70.6907 | 10 | 230 | 179.652 | 359.652 | 70.7 | 2500 | 700 | 30000 | 25264.6 | 35.7397 | 2526.46 | 706.907

# IfcWallStandardCase: default 360, Enveloppe 171035
In: Niveau 2
Type - Material: <aucun> 36 cm
Description: Enveloppe; Group: ...de stratigraphies = default; ...de matériaux et couleurs = Ivoire clair; ...de matériaux et couleurs - 1 = Ivoire clair; ...de matériaux et couleurs - 2 = Ivoire clair
__RECOGNIZE__ - ID: 171035; TPLG: 366; TPLG_OD: 9000; GENERATE: 1
CTLG_EXTERNAL_LINK - 0, DocType: 2; 0, Tag: 0; 0, Crc: 1977773087; 1, DocType: 2; 1, Tag: 100; 1, Crc: 1977773087; 2, DocType: 2; 2, Tag: 200; 2, Crc: 1977773087; 3, DocType: 9; 3, Tag: 0; 3, Crc: 1363053686
IFC_PSET_PolygonOffset - polygonOffsetFactor: 2; polygonOffsetUnits: 2
IFC_Pset_Alignment - Alignment: 0
IFC_Pset_Strat_Detail_Align - ExternalFace: 0
IFC_Pset_Caractéristiques - ID: 171035; Numérotation: 0430; Numéro niveau: 05; Titre niveau: Niveau 2; Stratigraphie: default [360,00]; Épaisseur: 36 cm; Épaisseur VARIABLE: no
IFC_Pset_Caractéristiques_FRUIT - Fruit: no; Taille: 0 cm
IFC_Pset_Géométrie - Forme en Élévation: rectangle; Longueur: 63.5455 cm; Hauteur: 225 cm; Cote: 1.42109e-12 cm
IFC_Pset_Géométrie_P1 (POINT initial) - Hauteur: 225 cm; Cote: 1.42109e-12 cm; Angle XY: 89.179 deg
IFC_Pset_Géométrie_P2 (POINT final) - Hauteur: 225 cm; Cote: 1.42109e-12 cm; Angle XY: 269.179 deg
IFC_Pset_Système de Référence Altimétrique_SUPÉRIEUR - NIVEAU: HAUT Niveau 2 (Mezzanine 49003); delta: -10 cm; delta (P1): -10 cm; delta (P2): -10 cm; sous Niveau: <aucun>
IFC_Pset_Système de Référence Altimétrique_INFÉRIEUR - NIVEAU: Niveau 2 (Niveau 2 13545); delta: 1.42109e-12 cm; delta (P1): 1.42109e-12 cm; delta (P2): 1.42109e-12 cm; sous Niveau: <aucun>
IFC_Pset_Données Métré - Longueur Pied: 63.5 cm; Longueur Tête: 63.5 cm; Hauteur Maximale: 225 cm; Hauteur Minimale: 225 cm; Surface en Plan: 2300 cm2; Surface Pied: 2300 cm2; Surface Tête: 2300 cm2; Surface de la Paroi: 14300 cm2; Volume: 510000 cm3
IFC_Pset_Matériaux - Face gauche: Ivoire clair; Face droite: Ivoire clair; Face latérale: Ivoire clair
Pset_WallCommon - Reference: default [360,00] (..\VERTICALES\Default\)
BaseQuantities - GrossVolume: 514718 cm3; NetVolume: 514718 cm3; NominalLength: 63.5455 cm; NominalWidth: 36 cm; NominalHeight: 225 cm; GrossFootprintArea: 2287.64 cm2; NetFootprintArea: 2287.64 cm2; GrossSideArea: 14297.7 cm2; NetSideArea: 14297.7 cm2

# IfcWallStandardCase: default 398 (10)
Type - Material: <aucun> 39.8 cm
Description: Enveloppe; Group: ...de stratigraphies = default; ...de matériaux et couleurs = Ivoire clair; ...de matériaux et couleurs - 1 = Ivoire clair; ...de matériaux et couleurs - 2 = Ivoire clair
__RECOGNIZE__ - TPLG: 366; TPLG_OD: 9000; GENERATE: 1
CTLG_EXTERNAL_LINK - 0, DocType: 2; 0, Tag: 0; 0, Crc: 1977773087; 1, DocType: 2; 1, Tag: 100; 1, Crc: 1977773087; 2, DocType: 2; 2, Tag: 200; 2, Crc: 1977773087; 3, DocType: 9; 3, Tag: 0; 3, Crc: 1261420166
IFC_PSET_PolygonOffset - polygonOffsetFactor: 2; polygonOffsetUnits: 2
IFC_Pset_Strat_Detail_Align - ExternalFace: 1
IFC_Pset_Caractéristiques - Stratigraphie: default [398,00]; Épaisseur: 39.8 cm; Épaisseur VARIABLE: no
IFC_Pset_Caractéristiques_FRUIT - Fruit: no; Taille: 0 cm
IFC_Pset_Géométrie - Forme en Élévation: rectangle
IFC_Pset_Système de Référence Altimétrique_SUPÉRIEUR - sous Niveau: <aucun>
IFC_Pset_Système de Référence Altimétrique_INFÉRIEUR - sous Niveau: <aucun>
IFC_Pset_Matériaux - Face gauche: Ivoire clair; Face droite: Ivoire clair; Face latérale: Ivoire clair
Pset_WallCommon - Reference: default [398,00] (..\VERTICALES\Default\)
BaseQuantities - NominalWidth: 39.8 cm
Name | In | __RECOGNIZE__, ID = IFC_Pset_Caractéristiques, ID | Alignment | Numérotation | Numéro niveau | Titre niveau | Longueur (cm) = NominalLength (cm) | IFC_Pset_Géométrie, Hauteur (cm) = IFC_Pset_Géométrie_P1 (POINT initial), Hauteur (cm) = IFC_Pset_Géométrie_P2 (POINT final), Hauteur (cm) = NominalHeight (cm) | IFC_Pset_Géométrie, Cote (cm) = IFC_Pset_Géométrie_P1 (POINT initial), Cote (cm) = IFC_Pset_Géométrie_P2 (POINT final), Cote (cm) = IFC_Pset_Système de Référence Altimétrique_INFÉRIEUR, delta (cm) = IFC_Pset_Système de Référence Altimétrique_INFÉRIEUR, delta (P1) (cm) = IFC_Pset_Système de Référence Altimétrique_INFÉRIEUR, delta (P2) (cm) | IFC_Pset_Géométrie_P1 (POINT initial), Angle XY (deg) | IFC_Pset_Géométrie_P2 (POINT final), Angle XY (deg) | IFC_Pset_Système de Référence Altimétrique_SUPÉRIEUR, NIVEAU | IFC_Pset_Système de Référence Altimétrique_SUPÉRIEUR, delta (cm) = IFC_Pset_Système de Référence Altimétrique_SUPÉRIEUR, delta (P1) (cm) = IFC_Pset_Système de Référence Altimétrique_SUPÉRIEUR, delta (P2) (cm) | IFC_Pset_Système de Référence Altimétrique_INFÉRIEUR, NIVEAU | Longueur Pied (cm) = Longueur Tête (cm) | Hauteur Maximale (cm) = Hauteur Minimale (cm) | Surface en Plan (cm2) = Surface Pied (cm2) = Surface Tête (cm2) | Surface de la Paroi (cm2) | Volume (cm3) | GrossVolume (cm3) | NetVolume (cm3) | GrossFootprintArea (cm2) = NetFootprintArea (cm2) | GrossSideArea (cm2) | NetSideArea (cm2)
Enveloppe 395922 | Rez-de-chaussée | 395922 | 0 | 0668 | 03 | Rez-de-chaussée | 251.571 | 479.808 | -2 | 179.731 | 359.731 | HAUT Rez-de-chaussée (Niveau 1 2343) | 0.0128504 | Rez-de-chaussée (Rez-de-chaussée 1047) | 251.6 | 479.8 | 10100 | 120700 | 4830000 | 4804089 | 2530765 | 10012.5 | 120706 | 63587.1
Enveloppe 449531 | Niveau 1 | 449531 | 0 | 0750 | 04 | Niveau 1 | 199.704 | 91.115 | 285 | 179.731 | 359.731 | HAUT Niveau 1 (Niveau 2 13545) | 6.75016e-12 | Niveau 1 (Niveau 1 2343) | 199.7 | 91.1 | 8000 | 18200 | 730000 | 724203 | 380294 | 7948.23 | 18196.1 | 9555.14
Enveloppe 448692 | Niveau 1 | 448692 | 0 | 0745 | 04 | Niveau 1 | 70.3426 | 285 | 2 | 179.959 | 359.959 | HAUT Niveau 1 (Niveau 2 13545) | -89.115 | Niveau 1 (Niveau 1 2343) | 70.3 | 285 | 2800 | 20000 | 800000 | 797897 | 797897 | 2799.64 | 20047.7 | 20047.7
Enveloppe 449511 | Niveau 1 | 449511 | 0 | 0749 | 04 | Niveau 1 | 73.5842 | 376.102 | 0.0128504 | 179.068 | 359.068 | HAUT Niveau 1 (Niveau 2 13545) | 6.75016e-12 | Niveau 1 (Niveau 1 2343) | 73.6 | 376.1 | 2900 | 27700 | 1110000 | 1101472 | 1101472 | 2928.65 | 27675.2 | 27675.2
Enveloppe 425816 | Niveau 1 | 425816 | 0 | 0718 | 04 | Niveau 1 | 249.999 | 91.115 | 285 | 179.959 | 359.959 | HAUT Niveau 1 (Niveau 2 13545) | 6.75016e-12 | Niveau 1 (Niveau 1 2343) | 250 | 91.1 | 10000 | 22800 | 910000 | 906589 | 558759 | 9949.95 | 22778.6 | 14039.2
Enveloppe 427750 | Niveau 1 | 427750 | 0 | 0733 | 04 | Niveau 1 | 39.2083 | 89.115 | 2 | 179.959 | 359.959 | HAUT Niveau 1 (Niveau 2 13545) | -285 | Niveau 1 (Niveau 1 2343) | 39.2 | 89.1 | 1600 | 3500 | 140000 | 139063 | 139063 | 1560.49 | 3494.05 | 3494.05
Enveloppe 442124 | Niveau 1 | 442124 | 1 | 0738 | 04 | Niveau 1 | 198.9 | 91.115 | 285 | 0.13248 | 180.132 | HAUT Niveau 1 (Niveau 2 13545) | 6.75016e-12 | Niveau 1 (Niveau 1 2343) | 198.9 | 91.1 | 8000 | 18100 | 720000 | 721285 | 377376 | 7916.2 | 18122.7 | 9481.82
Enveloppe 442125 | Niveau 1 | 442125 | 0 | 0739 | 04 | Niveau 1 | 180.038 | 91.115 | 285 | 179.288 | 359.288 | HAUT Niveau 1 (Niveau 2 13545) | 6.75016e-12 | Niveau 1 (Niveau 1 2343) | 180 | 91.1 | 7200 | 16400 | 660000 | 652886 | 308515 | 7165.52 | 16404.2 | 7751.64
Enveloppe 435690 | Niveau 1 | 435690 | 0 | 0734 | 04 | Niveau 1 | 41.2983 | 89.115 | 2 | 179.731 | 359.731 | HAUT Niveau 1 (Niveau 2 13545) | -285 | Niveau 1 (Niveau 1 2343) | 41.3 | 89.1 | 1600 | 3700 | 150000 | 146476 | 146476 | 1643.67 | 3680.3 | 3680.3
Enveloppe 435701 | Niveau 1 | 435701 | 0 | 0735 | 04 | Niveau 1 | 40.5896 | 89.115 | 2 | 179.959 | 359.959 | HAUT Niveau 1 (Niveau 2 13545) | -285 | Niveau 1 (Niveau 1 2343) | 40.6 | 89.1 | 1600 | 3600 | 140000 | 143962 | 143962 | 1615.47 | 3617.14 | 3617.14

# IfcWallStandardCase: default 400 (18)
Type - Material: <aucun> 40 cm
Description: Enveloppe; Group: ...de stratigraphies = default; ...de matériaux et couleurs = Ivoire clair; ...de matériaux et couleurs - 1 = Ivoire clair; ...de matériaux et couleurs - 2 = Ivoire clair
__RECOGNIZE__ - TPLG: 366; TPLG_OD: 9000; GENERATE: 1
CTLG_EXTERNAL_LINK - 0, DocType: 2; 0, Tag: 0; 0, Crc: 1977773087; 1, DocType: 2; 1, Tag: 100; 1, Crc: 1977773087; 2, DocType: 2; 2, Tag: 200; 2, Crc: 1977773087; 3, DocType: 9; 3, Tag: 0; 3, Crc: -1417892457
IFC_PSET_PolygonOffset - polygonOffsetFactor: 2; polygonOffsetUnits: 2
IFC_Pset_Caractéristiques - Stratigraphie: default [400,00]; Épaisseur: 40 cm
IFC_Pset_Caractéristiques_FRUIT - Fruit: no; Taille: 0 cm
IFC_Pset_Géométrie - Forme en Élévation: rectangle
IFC_Pset_Système de Référence Altimétrique_SUPÉRIEUR - sous Niveau: <aucun>
IFC_Pset_Système de Référence Altimétrique_INFÉRIEUR - sous Niveau: <aucun>
IFC_Pset_Matériaux - Face gauche: Ivoire clair; Face droite: Ivoire clair; Face latérale: Ivoire clair
Pset_WallCommon - Reference: default [400,00] (..\VERTICALES\Default\)
Name | In | __RECOGNIZE__, ID = IFC_Pset_Caractéristiques, ID | Alignment | ExternalFace | Numérotation | Numéro niveau | Titre niveau | Épaisseur VARIABLE | Longueur (cm) = NominalLength (cm) | IFC_Pset_Géométrie, Hauteur (cm) = IFC_Pset_Géométrie_P1 (POINT initial), Hauteur (cm) = IFC_Pset_Géométrie_P2 (POINT final), Hauteur (cm) = NominalHeight (cm) | IFC_Pset_Géométrie, Cote (cm) = IFC_Pset_Géométrie_P1 (POINT initial), Cote (cm) = IFC_Pset_Géométrie_P2 (POINT final), Cote (cm) = IFC_Pset_Système de Référence Altimétrique_INFÉRIEUR, delta (cm) = IFC_Pset_Système de Référence Altimétrique_INFÉRIEUR, delta (P1) (cm) = IFC_Pset_Système de Référence Altimétrique_INFÉRIEUR, delta (P2) (cm) | IFC_Pset_Géométrie_P1 (POINT initial), Angle XY (deg) | IFC_Pset_Géométrie_P2 (POINT final), Angle XY (deg) | IFC_Pset_Système de Référence Altimétrique_SUPÉRIEUR, NIVEAU | IFC_Pset_Système de Référence Altimétrique_SUPÉRIEUR, delta (cm) = IFC_Pset_Système de Référence Altimétrique_SUPÉRIEUR, delta (P1) (cm) = IFC_Pset_Système de Référence Altimétrique_SUPÉRIEUR, delta (P2) (cm) | IFC_Pset_Système de Référence Altimétrique_INFÉRIEUR, NIVEAU | Longueur Pied (cm) = Longueur Tête (cm) | Hauteur Maximale (cm) = Hauteur Minimale (cm) | Surface en Plan (cm2) = Surface Pied (cm2) = Surface Tête (cm2) | Surface de la Paroi (cm2) | Volume (cm3) | GrossVolume (cm3) | NetVolume (cm3) | NominalWidth (cm) | GrossFootprintArea (cm2) = NetFootprintArea (cm2) | GrossSideArea (cm2) | NetSideArea (cm2)
Enveloppe 327081 | Rez-de-Jardin | 327081 | 1 | 1 | 0558 | 02 | Rez-de-Jardin | no | 39.4066 | 291.413 | -1.94511e-11 | 89.847 | 269.847 | HAUT Rez-de-Jardin (Rez-de-chaussée 1047) | 0.0128504 | Rez-de-Jardin (Rez-de-Jardin 15545) | 39.4 | 291.4 | 1600 | 11500 | 460000 | 459344 | 459344 | 40 | 1576.26 | 11483.6 | 11483.6
Enveloppe 326500 | Rez-de-Jardin | 326500 | 0 | 1 | 0557 | 02 | Rez-de-Jardin | no | 37.8681 | 291.413 | -1.94511e-11 | 89.6286 | 269.629 | HAUT Rez-de-Jardin (Rez-de-chaussée 1047) | 0.0128504 | Rez-de-Jardin (Rez-de-Jardin 15545) | 37.9 | 291.4 | 1500 | 11000 | 440000 | 441411 | 441411 | 40 | 1514.72 | 11035.3 | 11035.3
Enveloppe 9974 | Rez-de-chaussée | 9974 | 0 | 0 | 0047 | 03 | Rez-de-chaussée | no | 27.2915 | 477.795 | 0.0128504 | 90.1355 | 270.136 | HAUT Rez-de-chaussée (Niveau 1 2343) | 0.0128504 | Rez-de-chaussée (Rez-de-chaussée 1047) | 27.3 | 477.8 | 1100 | 13000 | 520000 | 521590 | 521590 | 40 | 1091.66 | 13039.7 | 13039.7
Enveloppe 93783 | Niveau 1 | 93783 | 1 | 0 | 0215 | 04 | Niveau 1 | no | 82.4797 | 376.102 | 0.0128504 | 179.988 | 359.988 | HAUT Niveau 1 (Niveau 2 13545) | 0 | Niveau 1 (Niveau 1 2343) | 82.5 | 376.1 | 3300 | 31000 | 1240000 | 1240832 | 1240832 | 40 | 3299.19 | 31020.8 | 31020.8
Enveloppe 93767 | Niveau 1 | 93767 | 0 | 0 | 0213 | 04 | Niveau 1 | no | 400.234 | 376.102 | 0.0128504 | 0.123219 | 180.123 | HAUT Niveau 1 (Niveau 2 13545) | 0 | Niveau 1 (Niveau 1 2343) | 400.2 | 376.1 | 16000 | 150500 | 6020000 | 6021150 | 3562222 | 40 | 16009.3 | 150529 | 89055.5
Enveloppe 93778 | Niveau 1 | 93778 | 0 | 0 | 0214 | 04 | Niveau 1 | no | 134.504 | 376.102 | 0.0128504 | 0.653853 | 180.654 | HAUT Niveau 1 (Niveau 2 13545) | 0 | Niveau 1 (Niveau 1 2343) | 134.5 | 376.1 | 5400 | 50600 | 2020000 | 2023484 | 799010 | 40 | 5380.14 | 50587.1 | 19975.2
Enveloppe 93743 | Niveau 1 | 93743 | 1 | 0 | 0211 | 04 | Niveau 1 | no | 199.002 | 376.102 | 0.0128504 | 179.975 | 359.975 | HAUT Niveau 1 (Niveau 2 13545) | 0 | Niveau 1 (Niveau 1 2343) | 199 | 376.1 | 8000 | 74800 | 2990000 | 2993797 | 1770747 | 40 | 7960.06 | 74844.9 | 44268.7
Enveloppe 93762 | Niveau 1 | 93762 | 0 | 0 | 0212 | 04 | Niveau 1 | no | 101.72 | 376.102 | 0.0128504 | 1.04861 | 181.049 | HAUT Niveau 1 (Niveau 2 13545) | 0 | Niveau 1 (Niveau 1 2343) | 101.7 | 376.1 | 4100 | 38200 | 1530000 | 1530285 | 1530285 | 40 | 4068.8 | 38257.1 | 38257.1
Enveloppe 94725 | Niveau 1 | 94725 | 1 | 0 | 0235 | 04 | Niveau 1 | no | 31.1476 | 376.102 | 0.0128504 | 138.975 | 318.975 | HAUT Niveau 1 (Niveau 2 13545) | 0 | Niveau 1 (Niveau 1 2343) | 31.1 | 376.1 | 1200 | 11700 | 470000 | 468588 | 468588 | 40 | 1245.91 | 11714.7 | 11714.7
Enveloppe 94667 | Niveau 1 | 94667 | 1 | 0 | 0233 | 04 | Niveau 1 | no | 164.071 | 376.102 | 0.0128504 | 135.416 | 315.416 | HAUT Niveau 1 (Niveau 2 13545) | 0 | Niveau 1 (Niveau 1 2343) | 164.1 | 376.1 | 6600 | 61700 | 2470000 | 2468294 | 1255589 | 40 | 6562.83 | 61707.3 | 31389.7
Enveloppe 94726 | Niveau 1 | 94726 | 0 | 0 | 0236 | 04 | Niveau 1 | no | 199.964 | 376.102 | 0.0128504 | 45.1108 | 225.111 | HAUT Niveau 1 (Niveau 2 13545) | 0 | Niveau 1 (Niveau 1 2343) | 200 | 376.1 | 8000 | 75200 | 3010000 | 3008275 | 1806180 | 40 | 7998.56 | 75206.9 | 45154.5
Enveloppe 94737 | Niveau 1 | 94737 | 0 | 0 | 0237 | 04 | Niveau 1 | no | 233.431 | 376.102 | 0.0128504 | 90.2393 | 270.239 | HAUT Niveau 1 (Niveau 2 13545) | 0 | Niveau 1 (Niveau 1 2343) | 233.4 | 376.1 | 9300 | 87800 | 3510000 | 3511756 | 2629457 | 40 | 9337.24 | 87793.9 | 65736.4
Enveloppe 94586 | Niveau 1 | 94586 | 1 | 0 | 0229 | 04 | Niveau 1 | no | 207.752 | 376.102 | 0.0128504 | 89.5122 | 269.512 | HAUT Niveau 1 (Niveau 2 13545) | 0 | Niveau 1 (Niveau 1 2343) | 207.8 | 376.1 | 8300 | 78200 | 3130000 | 3125444 | 2535044 | 40 | 8310.09 | 78136.1 | 63376.1
Enveloppe 94939 | Niveau 1 | 94939 | 0 | 0 | 0242 | 04 | Niveau 1 | yes | 140.406 | 376.102 | 0.0128504 | 90.8599 | 270.86 | HAUT Niveau 1 (Niveau 2 13545) | 0 | Niveau 1 (Niveau 1 2343) | 140.4 | 376.1 | 5600 | 52800 | 2110000 | 2112273 | 803945 | 40 | 5616.22 | 52806.8 | 20098.6
Enveloppe 180171 | Niveau 2 | 180171 | 0 | 0 | 0470 | 05 | Niveau 2 | no | 102.032 | 22 | 208 | 90.1302 | 270.13 | HAUT Niveau 2 (Mezzanine 49003) | -5 | Niveau 2 (Niveau 2 13545) | 102 | 22 | 4100 | 2200 | 90000 | 89788.6 | 89788.6 | 40 | 4081.3 | 2244.71 | 2244.71
Enveloppe 150782 | Niveau 2 | 150782 | 0 | 0 | 0341 | 05 | Niveau 2 | no | 96.1029 | 235 | 1.42109e-12 | 1.07081 | 181.071 | HAUT Niveau 2 (Mezzanine 49003) | 0 | Niveau 2 (Niveau 2 13545) | 96.1 | 235 | 3800 | 22600 | 900000 | 903367 | 903367 | 40 | 3844.12 | 22584.2 | 22584.2
Enveloppe 158818 | Niveau 2 | 158818 | 1 | 0 | 0366 | 05 | Niveau 2 | no | 84.8406 | 235 | 1.42109e-12 | 179.684 | 359.684 | HAUT Niveau 2 (Mezzanine 49003) | 0 | Niveau 2 (Niveau 2 13545) | 84.8 | 235 | 3400 | 19900 | 800000 | 797502 | 797502 | 40 | 3393.62 | 19937.5 | 19937.5
Enveloppe 167914 | Niveau 2 | 167914 | 1 | 0 | 0411 | 05 | Niveau 2 | yes | 105.159 | 66 | 169 | 1.25818 | 181.258 | HAUT Niveau 2 (Mezzanine 49003) | 1.42109e-12 | Niveau 2 (Niveau 2 13545) | 105.2 | 66 | 4300 | 6900 | 280000 | 286163 | 286163 | 41.2309 | 4335.8 | 6940.49 | 6940.49

# IfcWallStandardCase: default 410 (2)
In: Rez-de-Jardin
Type - Material: <aucun> 41 cm
Description: Enveloppe; Group: ...de stratigraphies = default; ...de matériaux et couleurs = Ivoire clair; ...de matériaux et couleurs - 1 = Ivoire clair; ...de matériaux et couleurs - 2 = Ivoire clair
__RECOGNIZE__ - TPLG: 366; TPLG_OD: 9000; GENERATE: 1
CTLG_EXTERNAL_LINK - 0, DocType: 2; 0, Tag: 0; 0, Crc: 1977773087; 1, DocType: 2; 1, Tag: 100; 1, Crc: 1977773087; 2, DocType: 2; 2, Tag: 200; 2, Crc: 1977773087; 3, DocType: 9; 3, Tag: 0; 3, Crc: -1550708166
IFC_PSET_PolygonOffset - polygonOffsetFactor: 2; polygonOffsetUnits: 2
IFC_Pset_Strat_Detail_Align - ExternalFace: 1
IFC_Pset_Caractéristiques - Numéro niveau: 02; Titre niveau: Rez-de-Jardin; Stratigraphie: default [410,00]; Épaisseur: 41 cm; Épaisseur VARIABLE: no
IFC_Pset_Caractéristiques_FRUIT - Fruit: no; Taille: 0 cm
IFC_Pset_Géométrie - Forme en Élévation: rectangle; Hauteur: 287.4 cm; Cote: -1.94511e-11 cm
IFC_Pset_Géométrie_P1 (POINT initial) - Hauteur: 287.4 cm; Cote: -1.94511e-11 cm
IFC_Pset_Géométrie_P2 (POINT final) - Hauteur: 287.4 cm; Cote: -1.94511e-11 cm
IFC_Pset_Système de Référence Altimétrique_SUPÉRIEUR - NIVEAU: HAUT Rez-de-Jardin (Rez-de-chaussée 1047); delta: -4 cm; delta (P1): -4 cm; delta (P2): -4 cm; sous Niveau: <aucun>
IFC_Pset_Système de Référence Altimétrique_INFÉRIEUR - NIVEAU: Rez-de-Jardin (Rez-de-Jardin 15545); delta: -1.94511e-11 cm; delta (P1): -1.94511e-11 cm; delta (P2): -1.94511e-11 cm; sous Niveau: <aucun>
IFC_Pset_Données Métré - Hauteur Maximale: 287.4 cm; Hauteur Minimale: 287.4 cm
IFC_Pset_Matériaux - Face gauche: Ivoire clair; Face droite: Ivoire clair; Face latérale: Ivoire clair
Pset_WallCommon - Reference: default [410,00] (..\VERTICALES\Default\)
BaseQuantities - NominalWidth: 41 cm; NominalHeight: 287.4 cm
Name | __RECOGNIZE__, ID = IFC_Pset_Caractéristiques, ID | Alignment | Numérotation | Longueur (cm) = NominalLength (cm) | IFC_Pset_Géométrie_P1 (POINT initial), Angle XY (deg) | IFC_Pset_Géométrie_P2 (POINT final), Angle XY (deg) | Longueur Pied (cm) = Longueur Tête (cm) | Surface en Plan (cm2) = Surface Pied (cm2) = Surface Tête (cm2) | Surface de la Paroi (cm2) | Volume (cm3) | GrossVolume (cm3) = NetVolume (cm3) | GrossFootprintArea (cm2) = NetFootprintArea (cm2) | GrossSideArea (cm2) = NetSideArea (cm2)
Enveloppe 311246 | 311246 | 0 | 0548 | 40.3805 | 179.755 | 359.755 | 40.4 | 1700 | 11600 | 480000 | 475820 | 1655.6 | 11605.4
Enveloppe 310578 | 310578 | 1 | 0546 | 38.4104 | 179.126 | 359.126 | 38.4 | 1600 | 11000 | 450000 | 452605 | 1574.83 | 11039.2

# IfcWallStandardCase: default 450, Enveloppe 174079
In: Niveau 2
Type - Material: <aucun> 45 cm
Description: Enveloppe; Group: ...de stratigraphies = default; ...de matériaux et couleurs = Ivoire clair; ...de matériaux et couleurs - 1 = Ivoire clair; ...de matériaux et couleurs - 2 = Ivoire clair
__RECOGNIZE__ - ID: 174079; TPLG: 366; TPLG_OD: 9000; GENERATE: 1
CTLG_EXTERNAL_LINK - 0, DocType: 2; 0, Tag: 0; 0, Crc: 1977773087; 1, DocType: 2; 1, Tag: 100; 1, Crc: 1977773087; 2, DocType: 2; 2, Tag: 200; 2, Crc: 1977773087; 3, DocType: 9; 3, Tag: 0; 3, Crc: -2078066898
IFC_PSET_PolygonOffset - polygonOffsetFactor: 2; polygonOffsetUnits: 2
IFC_Pset_Alignment - Alignment: 1
IFC_Pset_Strat_Detail_Align - ExternalFace: 1
IFC_Pset_Caractéristiques - ID: 174079; Numérotation: 0442; Numéro niveau: 05; Titre niveau: Niveau 2; Stratigraphie: default [450,00]; Épaisseur: 45 cm; Épaisseur VARIABLE: yes
IFC_Pset_Caractéristiques_FRUIT - Fruit: no; Taille: 0 cm
IFC_Pset_Géométrie - Forme en Élévation: rectangle; Longueur: 103.676 cm; Hauteur: 19.5 cm; Cote: 228 cm
IFC_Pset_Géométrie_P1 (POINT initial) - Hauteur: 19.5 cm; Cote: 228 cm; Angle XY: 1.15194 deg
IFC_Pset_Géométrie_P2 (POINT final) - Hauteur: 19.5 cm; Cote: 228 cm; Angle XY: 181.152 deg
IFC_Pset_Système de Référence Altimétrique_SUPÉRIEUR - NIVEAU: HAUT Niveau 2 (Mezzanine 49003); delta: 12.5 cm; delta (P1): 12.5 cm; delta (P2): 12.5 cm; sous Niveau: <aucun>
IFC_Pset_Système de Référence Altimétrique_INFÉRIEUR - NIVEAU: Niveau 2 (Niveau 2 13545); delta: 228 cm; delta (P1): 228 cm; delta (P2): 228 cm; sous Niveau: <aucun>
IFC_Pset_Données Métré - Longueur Pied: 103.7 cm; Longueur Tête: 103.7 cm; Hauteur Maximale: 19.5 cm; Hauteur Minimale: 19.5 cm; Surface en Plan: 4700 cm2; Surface Pied: 4700 cm2; Surface Tête: 4700 cm2; Surface de la Paroi: 2000 cm2; Volume: 90000 cm3
IFC_Pset_Matériaux - Face gauche: Ivoire clair; Face droite: Ivoire clair; Face latérale: Ivoire clair
Pset_WallCommon - Reference: default [450,00] (..\VERTICALES\Default\)
BaseQuantities - GrossVolume: 91534.3 cm3; NetVolume: 91534.3 cm3; NominalLength: 103.676 cm; NominalWidth: 45.2762 cm; NominalHeight: 19.5 cm; GrossFootprintArea: 4694.07 cm2; NetFootprintArea: 4694.07 cm2; GrossSideArea: 2021.69 cm2; NetSideArea: 2021.69 cm2

# IfcWallStandardCase: default 480, Enveloppe 119076
In: Niveau 1
Type - Material: <aucun> 48 cm
Description: Enveloppe; Group: ...de stratigraphies = default; ...de matériaux et couleurs = Ivoire clair; ...de matériaux et couleurs - 1 = Ivoire clair; ...de matériaux et couleurs - 2 = Ivoire clair
__RECOGNIZE__ - ID: 119076; TPLG: 366; TPLG_OD: 9000; GENERATE: 1
CTLG_EXTERNAL_LINK - 0, DocType: 2; 0, Tag: 0; 0, Crc: 1977773087; 1, DocType: 2; 1, Tag: 100; 1, Crc: 1977773087; 2, DocType: 2; 2, Tag: 200; 2, Crc: 1977773087; 3, DocType: 9; 3, Tag: 0; 3, Crc: -1915288656
IFC_PSET_PolygonOffset - polygonOffsetFactor: 2; polygonOffsetUnits: 2
IFC_Pset_Alignment - Alignment: 0
IFC_Pset_Strat_Detail_Align - ExternalFace: 0
IFC_Pset_Caractéristiques - ID: 119076; Numérotation: 0284; Numéro niveau: 04; Titre niveau: Niveau 1; Stratigraphie: default [480,00]; Épaisseur: 48 cm; Épaisseur VARIABLE: no
IFC_Pset_Caractéristiques_FRUIT - Fruit: no; Taille: 0 cm
IFC_Pset_Géométrie - Forme en Élévation: rectangle; Longueur: 149.905 cm; Hauteur: 376.102 cm; Cote: 0.0128504 cm
IFC_Pset_Géométrie_P1 (POINT initial) - Hauteur: 376.102 cm; Cote: 0.0128504 cm; Angle XY: 90.4996 deg
IFC_Pset_Géométrie_P2 (POINT final) - Hauteur: 376.102 cm; Cote: 0.0128504 cm; Angle XY: 270.5 deg
IFC_Pset_Système de Référence Altimétrique_SUPÉRIEUR - NIVEAU: HAUT Niveau 1 (Niveau 2 13545); delta: 0 cm; delta (P1): 0 cm; delta (P2): 0 cm; sous Niveau: <aucun>
IFC_Pset_Système de Référence Altimétrique_INFÉRIEUR - NIVEAU: Niveau 1 (Niveau 1 2343); delta: 0.0128504 cm; delta (P1): 0.0128504 cm; delta (P2): 0.0128504 cm; sous Niveau: <aucun>
IFC_Pset_Données Métré - Longueur Pied: 149.9 cm; Longueur Tête: 149.9 cm; Hauteur Maximale: 376.1 cm; Hauteur Minimale: 376.1 cm; Surface en Plan: 7200 cm2; Surface Pied: 7200 cm2; Surface Tête: 7200 cm2; Surface de la Paroi: 56400 cm2; Volume: 2710000 cm3
IFC_Pset_Matériaux - Face gauche: Ivoire clair; Face droite: Ivoire clair; Face latérale: Ivoire clair
Pset_WallCommon - Reference: default [480,00] (..\VERTICALES\Default\)
BaseQuantities - GrossVolume: 2706220 cm3; NetVolume: 1246603 cm3; NominalLength: 149.905 cm; NominalWidth: 48 cm; NominalHeight: 376.102 cm; GrossFootprintArea: 7195.44 cm2; NetFootprintArea: 7195.44 cm2; GrossSideArea: 56379.6 cm2; NetSideArea: 25970.9 cm2

# IfcWallStandardCase: default 50 (4)
Type - Material: <aucun> 5 cm
Description: Enveloppe; Group: ...de stratigraphies = default; ...de matériaux et couleurs = Ivoire clair; ...de matériaux et couleurs - 1 = Ivoire clair; ...de matériaux et couleurs - 2 = Ivoire clair
__RECOGNIZE__ - TPLG: 366; TPLG_OD: 9000; GENERATE: 1
CTLG_EXTERNAL_LINK - 0, DocType: 2; 0, Tag: 0; 0, Crc: 1977773087; 1, DocType: 2; 1, Tag: 100; 1, Crc: 1977773087; 2, DocType: 2; 2, Tag: 200; 2, Crc: 1977773087; 3, DocType: 9; 3, Tag: 0; 3, Crc: 2139206608
IFC_PSET_PolygonOffset - polygonOffsetFactor: 2; polygonOffsetUnits: 2
IFC_Pset_Strat_Detail_Align - ExternalFace: 0
IFC_Pset_Caractéristiques - Stratigraphie: default [50,00]; Épaisseur: 5 cm; Épaisseur VARIABLE: no
IFC_Pset_Caractéristiques_FRUIT - Fruit: no; Taille: 0 cm
IFC_Pset_Géométrie - Forme en Élévation: rectangle
IFC_Pset_Système de Référence Altimétrique_SUPÉRIEUR - sous Niveau: <aucun>
IFC_Pset_Système de Référence Altimétrique_INFÉRIEUR - sous Niveau: <aucun>
IFC_Pset_Matériaux - Face gauche: Ivoire clair; Face droite: Ivoire clair; Face latérale: Ivoire clair
Pset_WallCommon - Reference: default [50,00] (..\VERTICALES\Default\)
BaseQuantities - NominalWidth: 5 cm
Name | In | __RECOGNIZE__, ID = IFC_Pset_Caractéristiques, ID | Alignment | Numérotation | Numéro niveau | Titre niveau | Longueur (cm) = NominalLength (cm) | IFC_Pset_Géométrie, Hauteur (cm) = IFC_Pset_Géométrie_P1 (POINT initial), Hauteur (cm) = IFC_Pset_Géométrie_P2 (POINT final), Hauteur (cm) = NominalHeight (cm) | IFC_Pset_Géométrie, Cote (cm) = IFC_Pset_Géométrie_P1 (POINT initial), Cote (cm) = IFC_Pset_Géométrie_P2 (POINT final), Cote (cm) = IFC_Pset_Système de Référence Altimétrique_INFÉRIEUR, delta (cm) = IFC_Pset_Système de Référence Altimétrique_INFÉRIEUR, delta (P1) (cm) = IFC_Pset_Système de Référence Altimétrique_INFÉRIEUR, delta (P2) (cm) | IFC_Pset_Géométrie_P1 (POINT initial), Angle XY (deg) | IFC_Pset_Géométrie_P2 (POINT final), Angle XY (deg) | IFC_Pset_Système de Référence Altimétrique_SUPÉRIEUR, NIVEAU | IFC_Pset_Système de Référence Altimétrique_SUPÉRIEUR, delta (cm) = IFC_Pset_Système de Référence Altimétrique_SUPÉRIEUR, delta (P1) (cm) = IFC_Pset_Système de Référence Altimétrique_SUPÉRIEUR, delta (P2) (cm) | IFC_Pset_Système de Référence Altimétrique_INFÉRIEUR, NIVEAU | Longueur Pied (cm) = Longueur Tête (cm) | Hauteur Maximale (cm) = Hauteur Minimale (cm) | Surface en Plan (cm2) = Surface Pied (cm2) = Surface Tête (cm2) | Surface de la Paroi (cm2) | Volume (cm3) | GrossVolume (cm3) | NetVolume (cm3) | GrossFootprintArea (cm2) = NetFootprintArea (cm2) | GrossSideArea (cm2) | NetSideArea (cm2)
Enveloppe 70804 | Rez-de-Jardin | 70804 | 0 | 0141 | 02 | Rez-de-Jardin | 20 | 291.413 | -1.94511e-11 | 92.2205 | 272.221 | HAUT Rez-de-Jardin (Rez-de-chaussée 1047) | 0.0128504 | Rez-de-Jardin (Rez-de-Jardin 15545) | 20 | 291.4 | 100 | 5800 | 30000 | 29141.3 | 29141.3 | 100 | 5828.26 | 5828.26
Enveloppe 52881 | Rez-de-Jardin | 52881 | 1 | 0076 | 02 | Rez-de-Jardin | 27.0953 | 291.413 | -1.94511e-11 | 0.436961 | 180.437 | HAUT Rez-de-Jardin (Rez-de-chaussée 1047) | 0.0128504 | Rez-de-Jardin (Rez-de-Jardin 15545) | 27.1 | 291.4 | 100 | 7900 | 40000 | 39479.6 | 39479.6 | 135.476 | 7895.93 | 7895.93
Enveloppe 55597 | Rez-de-Jardin | 55597 | 1 | 0101 | 02 | Rez-de-Jardin | 20 | 291.413 | -1.94511e-11 | 90.437 | 270.437 | HAUT Rez-de-Jardin (Rez-de-chaussée 1047) | 0.0128504 | Rez-de-Jardin (Rez-de-Jardin 15545) | 20 | 291.4 | 100 | 5800 | 30000 | 29141.3 | 29141.3 | 100 | 5828.26 | 5828.26
Enveloppe 152355 | Niveau 2 | 152355 | 1 | 0354 | 05 | Niveau 2 | 90.5932 | 235 | 1.42109e-12 | 90.674 | 270.674 | HAUT Niveau 2 (Mezzanine 49003) | 0 | Niveau 2 (Niveau 2 13545) | 90.6 | 235 | 500 | 21300 | 110000 | 106447 | 19199.7 | 452.966 | 21289.4 | 3839.94

# IfcWallStandardCase: default 52.8504028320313 (3)
In: Rez-de-chaussée
Type - Material: <aucun> 5.28504 cm
Description: Enveloppe; Group: ...de stratigraphies = default; ...de matériaux et couleurs = Ivoire clair; ...de matériaux et couleurs - 1 = Ivoire clair; ...de matériaux et couleurs - 2 = Ivoire clair
__RECOGNIZE__ - TPLG: 366; TPLG_OD: 9000; GENERATE: 1
CTLG_EXTERNAL_LINK - 0, DocType: 2; 0, Tag: 0; 0, Crc: 1977773087; 1, DocType: 2; 1, Tag: 100; 1, Crc: 1977773087; 2, DocType: 2; 2, Tag: 200; 2, Crc: 1977773087; 3, DocType: 9; 3, Tag: 0; 3, Crc: -568935291
IFC_PSET_PolygonOffset - polygonOffsetFactor: 2; polygonOffsetUnits: 2
IFC_Pset_Strat_Detail_Align - ExternalFace: 0
IFC_Pset_Caractéristiques - Numéro niveau: 03; Titre niveau: Rez-de-chaussée; Stratigraphie: default [52,85]; Épaisseur: 5.29 cm
IFC_Pset_Caractéristiques_FRUIT - Fruit: no; Taille: 0 cm
IFC_Pset_Géométrie - Forme en Élévation: rectangle
IFC_Pset_Système de Référence Altimétrique_SUPÉRIEUR - NIVEAU: HAUT Rez-de-chaussée (Niveau 1 2343); sous Niveau: <aucun>
IFC_Pset_Système de Référence Altimétrique_INFÉRIEUR - NIVEAU: Rez-de-chaussée (Rez-de-chaussée 1047); sous Niveau: <aucun>
IFC_Pset_Matériaux - Face gauche: Ivoire clair; Face droite: Ivoire clair; Face latérale: Ivoire clair
Pset_WallCommon - Reference: default [52,85] (..\VERTICALES\Default\)
Name | __RECOGNIZE__, ID = IFC_Pset_Caractéristiques, ID | Alignment | Numérotation | Épaisseur VARIABLE | Longueur (cm) = NominalLength (cm) | IFC_Pset_Géométrie, Hauteur (cm) = IFC_Pset_Géométrie_P1 (POINT initial), Hauteur (cm) = IFC_Pset_Géométrie_P2 (POINT final), Hauteur (cm) = NominalHeight (cm) | IFC_Pset_Géométrie, Cote (cm) = IFC_Pset_Géométrie_P1 (POINT initial), Cote (cm) = IFC_Pset_Géométrie_P2 (POINT final), Cote (cm) = IFC_Pset_Système de Référence Altimétrique_INFÉRIEUR, delta (cm) = IFC_Pset_Système de Référence Altimétrique_INFÉRIEUR, delta (P1) (cm) = IFC_Pset_Système de Référence Altimétrique_INFÉRIEUR, delta (P2) (cm) | IFC_Pset_Géométrie_P1 (POINT initial), Angle XY (deg) | IFC_Pset_Géométrie_P2 (POINT final), Angle XY (deg) | IFC_Pset_Système de Référence Altimétrique_SUPÉRIEUR, delta (cm) = IFC_Pset_Système de Référence Altimétrique_SUPÉRIEUR, delta (P1) (cm) = IFC_Pset_Système de Référence Altimétrique_SUPÉRIEUR, delta (P2) (cm) | Longueur Pied (cm) = Longueur Tête (cm) | Hauteur Maximale (cm) = Hauteur Minimale (cm) | Surface en Plan (cm2) = Surface Pied (cm2) = Surface Tête (cm2) | Surface de la Paroi (cm2) | Volume (cm3) | GrossVolume (cm3) | NetVolume (cm3) | NominalWidth (cm) | GrossFootprintArea (cm2) = NetFootprintArea (cm2) | GrossSideArea (cm2) | NetSideArea (cm2)
Enveloppe 33569 | 33569 | 0 | 0068 | no | 28.2646 | 271.483 | 0.0128504 | 4.14645 | 184.146 | -206.3 | 28.3 | 271.5 | 100 | 7700 | 40000 | 40561.2 | 40561.2 | 5.286 | 149.406 | 7673.33 | 7673.33
Enveloppe 42906 | 42906 | 1 | 0071 | yes | 194.841 | 117.908 | 235 | 89.2836 | 269.284 | -124.887 | 194.8 | 117.9 | 1000 | 23000 | 120000 | 121437 | 33112.5 | 5.286 | 1029.93 | 22973.3 | 6264.19
Enveloppe 3050 | 3050 | 1 | 0018 | yes | 35.8625 | 352.895 | 0.0128504 | 28.5626 | 208.563 | -124.887 | 35.9 | 352.9 | 200 | 12700 | 80000 | 75314.7 | 75314.7 | 5.95105 | 213.419 | 12655.7 | 12655.7

# IfcWallStandardCase: default 520 (6)
In: Niveau 2
Type - Material: <aucun> 52 cm
Description: Enveloppe; Group: ...de stratigraphies = default; ...de matériaux et couleurs = Ivoire clair; ...de matériaux et couleurs - 1 = Ivoire clair; ...de matériaux et couleurs - 2 = Ivoire clair
__RECOGNIZE__ - TPLG: 366; TPLG_OD: 9000; GENERATE: 1
CTLG_EXTERNAL_LINK - 0, DocType: 2; 0, Tag: 0; 0, Crc: 1977773087; 1, DocType: 2; 1, Tag: 100; 1, Crc: 1977773087; 2, DocType: 2; 2, Tag: 200; 2, Crc: 1977773087; 3, DocType: 9; 3, Tag: 0; 3, Crc: 627646136
IFC_PSET_PolygonOffset - polygonOffsetFactor: 2; polygonOffsetUnits: 2
IFC_Pset_Strat_Detail_Align - ExternalFace: 0
IFC_Pset_Caractéristiques - Numéro niveau: 05; Titre niveau: Niveau 2; Stratigraphie: default [520,00]; Épaisseur: 52 cm
IFC_Pset_Caractéristiques_FRUIT - Fruit: no; Taille: 0 cm
IFC_Pset_Géométrie - Forme en Élévation: rectangle; Cote: 1.42109e-12 cm
IFC_Pset_Géométrie_P1 (POINT initial) - Cote: 1.42109e-12 cm
IFC_Pset_Géométrie_P2 (POINT final) - Cote: 1.42109e-12 cm
IFC_Pset_Système de Référence Altimétrique_SUPÉRIEUR - NIVEAU: HAUT Niveau 2 (Mezzanine 49003); sous Niveau: <aucun>
IFC_Pset_Système de Référence Altimétrique_INFÉRIEUR - NIVEAU: Niveau 2 (Niveau 2 13545); delta: 1.42109e-12 cm; delta (P1): 1.42109e-12 cm; delta (P2): 1.42109e-12 cm; sous Niveau: <aucun>
IFC_Pset_Matériaux - Face gauche: Ivoire clair; Face droite: Ivoire clair; Face latérale: Ivoire clair
Pset_WallCommon - Reference: default [520,00] (..\VERTICALES\Default\)
Name | __RECOGNIZE__, ID = IFC_Pset_Caractéristiques, ID | Alignment | Numérotation | Épaisseur VARIABLE | Longueur (cm) = NominalLength (cm) | IFC_Pset_Géométrie, Hauteur (cm) = IFC_Pset_Géométrie_P1 (POINT initial), Hauteur (cm) = IFC_Pset_Géométrie_P2 (POINT final), Hauteur (cm) = Hauteur Maximale (cm) = Hauteur Minimale (cm) = NominalHeight (cm) | IFC_Pset_Géométrie_P1 (POINT initial), Angle XY (deg) | IFC_Pset_Géométrie_P2 (POINT final), Angle XY (deg) | delta (cm) = delta (P1) (cm) = delta (P2) (cm) | Longueur Pied (cm) = Longueur Tête (cm) | Surface en Plan (cm2) = Surface Pied (cm2) = Surface Tête (cm2) | Surface de la Paroi (cm2) | Volume (cm3) | GrossVolume (cm3) | NetVolume (cm3) | NominalWidth (cm) | GrossFootprintArea (cm2) = NetFootprintArea (cm2) | GrossSideArea (cm2) | NetSideArea (cm2)
Enveloppe 150989 | 150989 | 0 | 0345 | yes | 124.913 | 210 | 89.9993 | 269.999 | -25 | 124.9 | 6600 | 26200 | 1390000 | 1382820 | 1382820 | 52.7155 | 6584.86 | 26231.8 | 26231.8
Enveloppe 150804 | 150804 | 1 | 0342 | yes | 90.1381 | 240 | 90.674 | 270.674 | 5 | 90.1 | 4700 | 21600 | 1150000 | 1136315 | 1136315 | 52.5265 | 4734.64 | 21633.2 | 21633.2
Enveloppe 157808 | 157808 | 1 | 0361 | yes | 59.989 | 235 | 90.8156 | 270.816 | 0 | 60 | 3200 | 14100 | 750000 | 747162 | 747162 | 53 | 3179.41 | 14097.4 | 14097.4
Enveloppe 171969 | 171969 | 0 | 0435 | no | 77.3264 | 247.5 | 0.100251 | 180.1 | 12.5 | 77.3 | 4000 | 19100 | 990000 | 995191 | 196214 | 52 | 4020.97 | 19138.3 | 3773.34
Enveloppe 150384 | 150384 | 1 | 0329 | no | 191.512 | 235 | 179.747 | 359.747 | 3.37508e-12 | 191.5 | 9900 | 45000 | 2340000 | 2340279 | 1313098 | 52 | 9958.63 | 45005.4 | 25251.9
Enveloppe 171447 | 171447 | 0 | 0433 | no | 226.211 | 247.5 | 0.679731 | 180.68 | 12.5 | 226.2 | 11800 | 56000 | 2910000 | 2911330 | 2911330 | 52 | 11762.9 | 55987.1 | 55987.1

# IfcWallStandardCase: default 525 (4)
In: Niveau 2
Type - Material: <aucun> 52.5 cm
Description: Enveloppe; Group: ...de stratigraphies = default; ...de matériaux et couleurs = Ivoire clair; ...de matériaux et couleurs - 1 = Ivoire clair; ...de matériaux et couleurs - 2 = Ivoire clair
__RECOGNIZE__ - TPLG: 366; TPLG_OD: 9000; GENERATE: 1
CTLG_EXTERNAL_LINK - 0, DocType: 2; 0, Tag: 0; 0, Crc: 1977773087; 1, DocType: 2; 1, Tag: 100; 1, Crc: 1977773087; 2, DocType: 2; 2, Tag: 200; 2, Crc: 1977773087; 3, DocType: 9; 3, Tag: 0; 3, Crc: -160688278
IFC_PSET_PolygonOffset - polygonOffsetFactor: 2; polygonOffsetUnits: 2
IFC_Pset_Strat_Detail_Align - ExternalFace: 0
IFC_Pset_Caractéristiques - Numéro niveau: 05; Titre niveau: Niveau 2; Stratigraphie: default [525,00]; Épaisseur: 52.5 cm; Épaisseur VARIABLE: no
IFC_Pset_Caractéristiques_FRUIT - Fruit: no; Taille: 0 cm
IFC_Pset_Géométrie - Forme en Élévation: rectangle
IFC_Pset_Système de Référence Altimétrique_SUPÉRIEUR - NIVEAU: HAUT Niveau 2 (Mezzanine 49003); sous Niveau: <aucun>
IFC_Pset_Système de Référence Altimétrique_INFÉRIEUR - NIVEAU: Niveau 2 (Niveau 2 13545); sous Niveau: <aucun>
IFC_Pset_Matériaux - Face gauche: Ivoire clair; Face droite: Ivoire clair; Face latérale: Ivoire clair
Pset_WallCommon - Reference: default [525,00] (..\VERTICALES\Default\)
BaseQuantities - NominalWidth: 52.5 cm
Name | __RECOGNIZE__, ID = IFC_Pset_Caractéristiques, ID | Alignment | Numérotation | Longueur (cm) = NominalLength (cm) | IFC_Pset_Géométrie, Hauteur (cm) = IFC_Pset_Géométrie_P1 (POINT initial), Hauteur (cm) = IFC_Pset_Géométrie_P2 (POINT final), Hauteur (cm) = Hauteur Maximale (cm) = Hauteur Minimale (cm) = NominalHeight (cm) | IFC_Pset_Géométrie, Cote (cm) = IFC_Pset_Géométrie_P1 (POINT initial), Cote (cm) = IFC_Pset_Géométrie_P2 (POINT final), Cote (cm) = IFC_Pset_Système de Référence Altimétrique_INFÉRIEUR, delta (cm) = IFC_Pset_Système de Référence Altimétrique_INFÉRIEUR, delta (P1) (cm) = IFC_Pset_Système de Référence Altimétrique_INFÉRIEUR, delta (P2) (cm) | IFC_Pset_Géométrie_P1 (POINT initial), Angle XY (deg) | IFC_Pset_Géométrie_P2 (POINT final), Angle XY (deg) | IFC_Pset_Système de Référence Altimétrique_SUPÉRIEUR, delta (cm) = IFC_Pset_Système de Référence Altimétrique_SUPÉRIEUR, delta (P1) (cm) = IFC_Pset_Système de Référence Altimétrique_SUPÉRIEUR, delta (P2) (cm) | Longueur Pied (cm) = Longueur Tête (cm) | Surface en Plan (cm2) = Surface Pied (cm2) = Surface Tête (cm2) | Surface de la Paroi (cm2) | Volume (cm3) | GrossVolume (cm3) = NetVolume (cm3) | GrossFootprintArea (cm2) = NetFootprintArea (cm2) | GrossSideArea (cm2) = NetSideArea (cm2)
Enveloppe 152192 | 152192 | 1 | 0352 | 41.7183 | 235 | 1.42109e-12 | 91.555 | 271.555 | 0 | 41.7 | 2200 | 9800 | 520000 | 514699 | 2190.21 | 9803.79
Enveloppe 153307 | 153307 | 0 | 0359 | 159.896 | 10 | 225 | 0.0515293 | 180.052 | 0 | 159.9 | 8500 | 1600 | 80000 | 83945.5 | 8394.55 | 1598.96
Enveloppe 150479 | 150479 | 0 | 0330 | 26.0637 | 235 | 1.42109e-12 | 0.564788 | 180.565 | 0 | 26.1 | 1400 | 6100 | 320000 | 321561 | 1368.35 | 6124.97
Enveloppe 150662 | 150662 | 0 | 0335 | 68.0388 | 225 | 1.42109e-12 | 0.0515293 | 180.052 | -10 | 68 | 3600 | 15300 | 810000 | 803708 | 3572.04 | 15308.7

# IfcWallStandardCase: default 536.174377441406 (3)
In: Rez-de-chaussée
Type - Material: <aucun> 53.6174 cm
Description: Enveloppe; Group: ...de stratigraphies = default; ...de matériaux et couleurs = Ivoire clair; ...de matériaux et couleurs - 1 = Ivoire clair; ...de matériaux et couleurs - 2 = Ivoire clair
__RECOGNIZE__ - TPLG: 366; TPLG_OD: 9000; GENERATE: 1
CTLG_EXTERNAL_LINK - 0, DocType: 2; 0, Tag: 0; 0, Crc: 1977773087; 1, DocType: 2; 1, Tag: 100; 1, Crc: 1977773087; 2, DocType: 2; 2, Tag: 200; 2, Crc: 1977773087; 3, DocType: 9; 3, Tag: 0; 3, Crc: -994478623
IFC_PSET_PolygonOffset - polygonOffsetFactor: 2; polygonOffsetUnits: 2
IFC_Pset_Alignment - Alignment: 0
IFC_Pset_Strat_Detail_Align - ExternalFace: 0
IFC_Pset_Caractéristiques - Numéro niveau: 03; Titre niveau: Rez-de-chaussée; Stratigraphie: default [536,17]; Épaisseur: 53.62 cm; Épaisseur VARIABLE: no
IFC_Pset_Caractéristiques_FRUIT - Fruit: no; Taille: 0 cm
IFC_Pset_Géométrie - Forme en Élévation: rectangle
IFC_Pset_Géométrie_P1 (POINT initial) - Angle XY: 0.0515293 deg
IFC_Pset_Géométrie_P2 (POINT final) - Angle XY: 180.052 deg
IFC_Pset_Système de Référence Altimétrique_SUPÉRIEUR - NIVEAU: HAUT Rez-de-chaussée (Niveau 1 2343); delta: -199.787 cm; delta (P1): -199.787 cm; delta (P2): -199.787 cm; sous Niveau: <aucun>
IFC_Pset_Système de Référence Altimétrique_INFÉRIEUR - NIVEAU: Rez-de-chaussée (Rez-de-chaussée 1047); sous Niveau: <aucun>
IFC_Pset_Matériaux - Face gauche: Ivoire clair; Face droite: Ivoire clair; Face latérale: Ivoire clair
Pset_WallCommon - Reference: default [536,17] (..\VERTICALES\Default\)
BaseQuantities - NominalWidth: 53.6174 cm
Name | __RECOGNIZE__, ID = IFC_Pset_Caractéristiques, ID | Numérotation | Longueur (cm) = NominalLength (cm) | IFC_Pset_Géométrie, Hauteur (cm) = IFC_Pset_Géométrie_P1 (POINT initial), Hauteur (cm) = IFC_Pset_Géométrie_P2 (POINT final), Hauteur (cm) = NominalHeight (cm) | IFC_Pset_Géométrie, Cote (cm) = IFC_Pset_Géométrie_P1 (POINT initial), Cote (cm) = IFC_Pset_Géométrie_P2 (POINT final), Cote (cm) = delta (cm) = delta (P1) (cm) = delta (P2) (cm) | Longueur Pied (cm) = Longueur Tête (cm) | Hauteur Maximale (cm) = Hauteur Minimale (cm) | Surface en Plan (cm2) = Surface Pied (cm2) = Surface Tête (cm2) | Surface de la Paroi (cm2) | Volume (cm3) | GrossVolume (cm3) | NetVolume (cm3) | GrossFootprintArea (cm2) = NetFootprintArea (cm2) | GrossSideArea (cm2) | NetSideArea (cm2)
Enveloppe 5982 | 5982 | 0036 | 156.459 | 277.995 | 0.0128504 | 156.5 | 278 | 8500 | 43500 | 2350000 | 2332082 | 1404358 | 8388.92 | 43494.8 | 26192.2
Enveloppe 3292 | 3292 | 0025 | 155.999 | 277.995 | 0.0128504 | 156 | 278 | 8400 | 43400 | 2340000 | 2325234 | 1287093 | 8364.29 | 43367.1 | 24005.1
Enveloppe 31373 | 31373 | 0063 | 226.365 | 72.9954 | 205.013 | 226.4 | 73 | 12200 | 16500 | 890000 | 885952 | 885952 | 12137.1 | 16523.6 | 16523.6

# IfcWallStandardCase: default 540 (15)
Type - Material: <aucun> 54 cm
Description: Enveloppe; Group: ...de stratigraphies = default; ...de matériaux et couleurs = Ivoire clair; ...de matériaux et couleurs - 1 = Ivoire clair; ...de matériaux et couleurs - 2 = Ivoire clair
__RECOGNIZE__ - TPLG: 366; TPLG_OD: 9000; GENERATE: 1
CTLG_EXTERNAL_LINK - 0, DocType: 2; 0, Tag: 0; 0, Crc: 1977773087; 1, DocType: 2; 1, Tag: 100; 1, Crc: 1977773087; 2, DocType: 2; 2, Tag: 200; 2, Crc: 1977773087; 3, DocType: 9; 3, Tag: 0; 3, Crc: -1678105643
IFC_PSET_PolygonOffset - polygonOffsetFactor: 2; polygonOffsetUnits: 2
IFC_Pset_Strat_Detail_Align - ExternalFace: 0
IFC_Pset_Caractéristiques - Stratigraphie: default [540,00]; Épaisseur: 54 cm
IFC_Pset_Caractéristiques_FRUIT - Fruit: no; Taille: 0 cm
IFC_Pset_Géométrie - Forme en Élévation: rectangle
IFC_Pset_Système de Référence Altimétrique_SUPÉRIEUR - delta: 0 cm; delta (P1): 0 cm; delta (P2): 0 cm; sous Niveau: <aucun>
IFC_Pset_Système de Référence Altimétrique_INFÉRIEUR - sous Niveau: <aucun>
IFC_Pset_Matériaux - Face gauche: Ivoire clair; Face droite: Ivoire clair; Face latérale: Ivoire clair
Pset_WallCommon - Reference: default [540,00] (..\VERTICALES\Default\)
Name | In | __RECOGNIZE__, ID = IFC_Pset_Caractéristiques, ID | Alignment | Numérotation | Numéro niveau | Titre niveau | Épaisseur VARIABLE | Longueur (cm) = NominalLength (cm) | IFC_Pset_Géométrie, Hauteur (cm) = IFC_Pset_Géométrie_P1 (POINT initial), Hauteur (cm) = IFC_Pset_Géométrie_P2 (POINT final), Hauteur (cm) = NominalHeight (cm) | IFC_Pset_Géométrie, Cote (cm) = IFC_Pset_Géométrie_P1 (POINT initial), Cote (cm) = IFC_Pset_Géométrie_P2 (POINT final), Cote (cm) = delta (cm) = delta (P1) (cm) = delta (P2) (cm) | IFC_Pset_Géométrie_P1 (POINT initial), Angle XY (deg) | IFC_Pset_Géométrie_P2 (POINT final), Angle XY (deg) | IFC_Pset_Système de Référence Altimétrique_SUPÉRIEUR, NIVEAU | IFC_Pset_Système de Référence Altimétrique_INFÉRIEUR, NIVEAU | Longueur Pied (cm) = Longueur Tête (cm) | Hauteur Maximale (cm) = Hauteur Minimale (cm) | Surface en Plan (cm2) = Surface Pied (cm2) = Surface Tête (cm2) | Surface de la Paroi (cm2) | Volume (cm3) | GrossVolume (cm3) | NetVolume (cm3) | NominalWidth (cm) | GrossFootprintArea (cm2) = NetFootprintArea (cm2) | GrossSideArea (cm2) | NetSideArea (cm2)
Enveloppe 93014 | Niveau 1 | 93014 | 0 | 0197 | 04 | Niveau 1 | yes | 264.224 | 376.102 | 0.0128504 | 90.174 | 270.174 | HAUT Niveau 1 (Niveau 2 13545) | Niveau 1 (Niveau 1 2343) | 264.2 | 376.1 | 14400 | 99400 | 5470000 | 5424382 | 5424382 | 54.5849 | 14422.6 | 99375.2 | 99375.2
Enveloppe 92836 | Niveau 1 | 92836 | 1 | 0194 | 04 | Niveau 1 | yes | 86.5542 | 376.102 | 0.0128504 | 0.187813 | 180.188 | HAUT Niveau 1 (Niveau 2 13545) | Niveau 1 (Niveau 1 2343) | 86.6 | 376.1 | 4800 | 32600 | 1790000 | 1798727 | 1798727 | 55.255 | 4782.55 | 32553.2 | 32553.2
Enveloppe 93926 | Niveau 1 | 93926 | 1 | 0220 | 04 | Niveau 1 | yes | 43.9435 | 376.102 | 0.0128504 | 0.100251 | 180.1 | HAUT Niveau 1 (Niveau 2 13545) | Niveau 1 (Niveau 1 2343) | 43.9 | 376.1 | 2500 | 16500 | 940000 | 935157 | 935157 | 56.5827 | 2486.44 | 16527.3 | 16527.3
Enveloppe 106840 | Niveau 1 | 106840 | 1 | 0273 | 04 | Niveau 1 | yes | 85.384 | 376.102 | 0.0128504 | 0.064788 | 180.065 | HAUT Niveau 1 (Niveau 2 13545) | Niveau 1 (Niveau 1 2343) | 85.4 | 376.1 | 4600 | 32100 | 1730000 | 1735921 | 1735921 | 54.0564 | 4615.56 | 32113.1 | 32113.1
Enveloppe 111345 | Niveau 1 | 111345 | 1 | 0276 | 04 | Niveau 1 | yes | 128.047 | 140.615 | 235.5 | 0.187813 | 180.188 | HAUT Niveau 1 (Niveau 2 13545) | Niveau 1 (Niveau 1 2343) | 128 | 140.6 | 7100 | 18000 | 990000 | 991393 | 991393 | 55.061 | 7050.4 | 18005.4 | 18005.4
Enveloppe 111426 | Niveau 1 | 111426 | 1 | 0277 | 04 | Niveau 1 | yes | 169.619 | 376.102 | 0.0128504 | 0.243532 | 180.244 | HAUT Niveau 1 (Niveau 2 13545) | Niveau 1 (Niveau 1 2343) | 169.6 | 376.1 | 9300 | 63800 | 3510000 | 3496253 | 3496253 | 54.8054 | 9296.02 | 63794 | 63794
Enveloppe 106894 | Niveau 1 | 106894 | 1 | 0275 | 04 | Niveau 1 | yes | 125.194 | 143.615 | 232.5 | 0.064788 | 180.065 | HAUT Niveau 1 (Niveau 2 13545) | Niveau 1 (Niveau 1 2343) | 125.2 | 143.6 | 6800 | 18000 | 970000 | 974249 | 974249 | 54.186 | 6783.75 | 17979.7 | 17979.7
Enveloppe 115726 | Niveau 1 | 115726 | 1 | 0279 | 04 | Niveau 1 | yes | 34.4528 | 376.102 | 0.0128504 | 0.100251 | 180.1 | HAUT Niveau 1 (Niveau 2 13545) | Niveau 1 (Niveau 1 2343) | 34.5 | 376.1 | 1900 | 13000 | 730000 | 722885 | 722885 | 55.7877 | 1922.04 | 12957.8 | 12957.8
Enveloppe 116206 | Niveau 1 | 116206 | 1 | 0282 | 04 | Niveau 1 | yes | 97.785 | 145.115 | 231 | 0.100251 | 180.1 | HAUT Niveau 1 (Niveau 2 13545) | Niveau 1 (Niveau 1 2343) | 97.8 | 145.1 | 5500 | 14200 | 790000 | 795638 | 795638 | 56.07 | 5482.81 | 14190.1 | 14190.1
Enveloppe 94148 | Niveau 1 | 94148 | 0 | 0223 | 04 | Niveau 1 | no | 174.04 | 376.102 | 0.0128504 | 90.1529 | 270.153 | HAUT Niveau 1 (Niveau 2 13545) | Niveau 1 (Niveau 1 2343) | 174 | 376.1 | 9400 | 65400 | 3530000 | 3534673 | 3534673 | 54 | 9398.17 | 65456.9 | 65456.9
Enveloppe 128676 | Niveau 1 | 128676 | 0 | 0298 | 04 | Niveau 1 | yes | 118.064 | 142.615 | 233.5 | 90.1529 | 270.153 | HAUT Niveau 1 (Niveau 2 13545) | Niveau 1 (Niveau 1 2343) | 118.1 | 142.6 | 6400 | 16800 | 910000 | 909239 | 909239 | 54 | 6375.48 | 16837.8 | 16837.8
Enveloppe 101937 | Niveau 1 | 101937 | 0 | 0249 | 04 | Niveau 1 | yes | 157.389 | 168 | 208.115 | 0.0515293 | 180.052 | HAUT Niveau 1 (Niveau 2 13545) | Niveau 1 (Niveau 1 2343) | 157.4 | 168 | 8500 | 26400 | 1430000 | 1427833 | 1427833 | 54 | 8499.01 | 26441.4 | 26441.4
Enveloppe 93139 | Niveau 1 | 93139 | 0 | 0201 | 04 | Niveau 1 | no | 191.813 | 376.102 | 0.0128504 | 0.0515293 | 180.052 | HAUT Niveau 1 (Niveau 2 13545) | Niveau 1 (Niveau 1 2343) | 191.8 | 376.1 | 10400 | 72100 | 3890000 | 3895622 | 2773919 | 54 | 10357.9 | 72141.1 | 51368.9
Enveloppe 95721 | Niveau 1 | 95721 | 0 | 0246 | 04 | Niveau 1 | no | 190.441 | 376.102 | 0.0128504 | 0.0515293 | 180.052 | HAUT Niveau 1 (Niveau 2 13545) | Niveau 1 (Niveau 1 2343) | 190.4 | 376.1 | 10200 | 71600 | 3870000 | 3867771 | 2433801 | 54 | 10283.8 | 71625.4 | 45070.4
Enveloppe 157798 | Niveau 2 | 157798 | 1 | 0360 | 05 | Niveau 2 | yes | 58.4365 | 235 | 1.42109e-12 | 90.8156 | 270.816 | HAUT Niveau 2 (Mezzanine 49003) | Niveau 2 (Niveau 2 13545) | 58.4 | 235 | 3200 | 13700 | 740000 | 745304 | 745304 | 54.2727 | 3171.51 | 13732.6 | 13732.6

# IfcWallStandardCase: default 544 (3)
In: Rez-de-chaussée
Type - Material: <aucun> 54.4 cm
Description: Enveloppe; Group: ...de stratigraphies = default; ...de matériaux et couleurs = Ivoire clair; ...de matériaux et couleurs - 1 = Ivoire clair; ...de matériaux et couleurs - 2 = Ivoire clair
__RECOGNIZE__ - TPLG: 366; TPLG_OD: 9000; GENERATE: 1
CTLG_EXTERNAL_LINK - 0, DocType: 2; 0, Tag: 0; 0, Crc: 1977773087; 1, DocType: 2; 1, Tag: 100; 1, Crc: 1977773087; 2, DocType: 2; 2, Tag: 200; 2, Crc: 1977773087; 3, DocType: 9; 3, Tag: 0; 3, Crc: 1903528590
IFC_PSET_PolygonOffset - polygonOffsetFactor: 2; polygonOffsetUnits: 2
IFC_Pset_Alignment - Alignment: 1
IFC_Pset_Strat_Detail_Align - ExternalFace: 0
IFC_Pset_Caractéristiques - Numéro niveau: 03; Titre niveau: Rez-de-chaussée; Stratigraphie: default [544,00]; Épaisseur: 54.4 cm
IFC_Pset_Caractéristiques_FRUIT - Fruit: no; Taille: 0 cm
IFC_Pset_Géométrie - Forme en Élévation: rectangle; Cote: 0.0128504 cm
IFC_Pset_Géométrie_P1 (POINT initial) - Cote: 0.0128504 cm; Angle XY: 0.201098 deg
IFC_Pset_Géométrie_P2 (POINT final) - Cote: 0.0128504 cm; Angle XY: 180.201 deg
IFC_Pset_Système de Référence Altimétrique_SUPÉRIEUR - NIVEAU: HAUT Rez-de-chaussée (Niveau 1 2343); sous Niveau: <aucun>
IFC_Pset_Système de Référence Altimétrique_INFÉRIEUR - NIVEAU: Rez-de-chaussée (Rez-de-chaussée 1047); delta: 0.0128504 cm; delta (P1): 0.0128504 cm; delta (P2): 0.0128504 cm; sous Niveau: <aucun>
IFC_Pset_Matériaux - Face gauche: Ivoire clair; Face droite: Ivoire clair; Face latérale: Ivoire clair
Pset_WallCommon - Reference: default [544,00] (..\VERTICALES\Default\)
Name | __RECOGNIZE__, ID = IFC_Pset_Caractéristiques, ID | Numérotation | Épaisseur VARIABLE | Longueur (cm) = NominalLength (cm) | IFC_Pset_Géométrie, Hauteur (cm) = IFC_Pset_Géométrie_P1 (POINT initial), Hauteur (cm) = IFC_Pset_Géométrie_P2 (POINT final), Hauteur (cm) = NominalHeight (cm) | delta (cm) = delta (P1) (cm) = delta (P2) (cm) | Longueur Pied (cm) = Longueur Tête (cm) | Hauteur Maximale (cm) = Hauteur Minimale (cm) | Surface en Plan (cm2) = Surface Pied (cm2) = Surface Tête (cm2) | Surface de la Paroi (cm2) | Volume (cm3) | GrossVolume (cm3) | NetVolume (cm3) | NominalWidth (cm) | GrossFootprintArea (cm2) = NetFootprintArea (cm2) | GrossSideArea (cm2) | NetSideArea (cm2)
Enveloppe 28084 | 28084 | 0058 | yes | 42.5499 | 397.695 | -80.0871 | 42.5 | 397.7 | 2300 | 16900 | 930000 | 924172 | 924172 | 54.614 | 2323.82 | 16921.9 | 16921.9
Enveloppe 2511 | 2511 | 0004 | yes | 45.7842 | 397.695 | -80.0871 | 45.8 | 397.7 | 2500 | 18200 | 1020000 | 1012058 | 1012058 | 55.5826 | 2544.81 | 18208.2 | 18208.2
Enveloppe 2536 | 2536 | 0005 | no | 268.312 | 399.097 | -78.6853 | 268.3 | 399.1 | 14500 | 107100 | 5780000 | 5825301 | 4941464 | 54.4 | 14596.2 | 107083 | 90835.7

# IfcWallStandardCase: default 545, Enveloppe 92747
In: Niveau 1
Type - Material: <aucun> 54.5 cm
Description: Enveloppe; Group: ...de stratigraphies = default; ...de matériaux et couleurs = Ivoire clair; ...de matériaux et couleurs - 1 = Ivoire clair; ...de matériaux et couleurs - 2 = Ivoire clair
__RECOGNIZE__ - ID: 92747; TPLG: 366; TPLG_OD: 9000; GENERATE: 1
CTLG_EXTERNAL_LINK - 0, DocType: 2; 0, Tag: 0; 0, Crc: 1977773087; 1, DocType: 2; 1, Tag: 100; 1, Crc: 1977773087; 2, DocType: 2; 2, Tag: 200; 2, Crc: 1977773087; 3, DocType: 9; 3, Tag: 0; 3, Crc: 380751038
IFC_PSET_PolygonOffset - polygonOffsetFactor: 2; polygonOffsetUnits: 2
IFC_Pset_Alignment - Alignment: 0
IFC_Pset_Strat_Detail_Align - ExternalFace: 1
IFC_Pset_Caractéristiques - ID: 92747; Numérotation: 0192; Numéro niveau: 04; Titre niveau: Niveau 1; Stratigraphie: default [545,00]; Épaisseur: 54.5 cm; Épaisseur VARIABLE: no
IFC_Pset_Caractéristiques_FRUIT - Fruit: no; Taille: 0 cm
IFC_Pset_Géométrie - Forme en Élévation: rectangle; Longueur: 491.031 cm; Hauteur: 376.102 cm; Cote: 0.0128504 cm
IFC_Pset_Géométrie_P1 (POINT initial) - Hauteur: 376.102 cm; Cote: 0.0128504 cm; Angle XY: 0.146679 deg
IFC_Pset_Géométrie_P2 (POINT final) - Hauteur: 376.102 cm; Cote: 0.0128504 cm; Angle XY: 180.147 deg
IFC_Pset_Système de Référence Altimétrique_SUPÉRIEUR - NIVEAU: HAUT Niveau 1 (Niveau 2 13545); delta: 0 cm; delta (P1): 0 cm; delta (P2): 0 cm; sous Niveau: <aucun>
IFC_Pset_Système de Référence Altimétrique_INFÉRIEUR - NIVEAU: Niveau 1 (Niveau 1 2343); delta: 0.0128504 cm; delta (P1): 0.0128504 cm; delta (P2): 0.0128504 cm; sous Niveau: <aucun>
IFC_Pset_Données Métré - Longueur Pied: 491 cm; Longueur Tête: 491 cm; Hauteur Maximale: 376.1 cm; Hauteur Minimale: 376.1 cm; Surface en Plan: 27000 cm2; Surface Pied: 27000 cm2; Surface Tête: 27000 cm2; Surface de la Paroi: 184700 cm2; Volume: 10160000 cm3
IFC_Pset_Matériaux - Face gauche: Ivoire clair; Face droite: Ivoire clair; Face latérale: Ivoire clair
Pset_WallCommon - Reference: default [545,00] (..\VERTICALES\Default\)
BaseQuantities - GrossVolume: 10064942 cm3; NetVolume: 8443894 cm3; NominalLength: 491.031 cm; NominalWidth: 54.5 cm; NominalHeight: 376.102 cm; GrossFootprintArea: 26761.2 cm2; NetFootprintArea: 26761.2 cm2; GrossSideArea: 184678 cm2; NetSideArea: 154934 cm2

# IfcWallStandardCase: default 547, Enveloppe 105190
In: Niveau 1
Type - Material: <aucun> 54.7 cm
Description: Enveloppe; Group: ...de stratigraphies = default; ...de matériaux et couleurs = Ivoire clair; ...de matériaux et couleurs - 1 = Ivoire clair; ...de matériaux et couleurs - 2 = Ivoire clair
__RECOGNIZE__ - ID: 105190; TPLG: 366; TPLG_OD: 9000; GENERATE: 1
CTLG_EXTERNAL_LINK - 0, DocType: 2; 0, Tag: 0; 0, Crc: 1977773087; 1, DocType: 2; 1, Tag: 100; 1, Crc: 1977773087; 2, DocType: 2; 2, Tag: 200; 2, Crc: 1977773087; 3, DocType: 9; 3, Tag: 0; 3, Crc: -126434913
IFC_PSET_PolygonOffset - polygonOffsetFactor: 2; polygonOffsetUnits: 2
IFC_Pset_Alignment - Alignment: 0
IFC_Pset_Strat_Detail_Align - ExternalFace: 0
IFC_Pset_Caractéristiques - ID: 105190; Numérotation: 0272; Numéro niveau: 04; Titre niveau: Niveau 1; Stratigraphie: default [547,00]; Épaisseur: 54.7 cm; Épaisseur VARIABLE: no
IFC_Pset_Caractéristiques_FRUIT - Fruit: no; Taille: 0 cm
IFC_Pset_Géométrie - Forme en Élévation: rectangle; Longueur: 55.3819 cm; Hauteur: 376.102 cm; Cote: 0.0128504 cm
IFC_Pset_Géométrie_P1 (POINT initial) - Hauteur: 376.102 cm; Cote: 0.0128504 cm; Angle XY: 90.174 deg
IFC_Pset_Géométrie_P2 (POINT final) - Hauteur: 376.102 cm; Cote: 0.0128504 cm; Angle XY: 270.174 deg
IFC_Pset_Système de Référence Altimétrique_SUPÉRIEUR - NIVEAU: HAUT Niveau 1 (Niveau 2 13545); delta: 0 cm; delta (P1): 0 cm; delta (P2): 0 cm; sous Niveau: <aucun>
IFC_Pset_Système de Référence Altimétrique_INFÉRIEUR - NIVEAU: Niveau 1 (Niveau 1 2343); delta: 0.0128504 cm; delta (P1): 0.0128504 cm; delta (P2): 0.0128504 cm; sous Niveau: <aucun>
IFC_Pset_Données Métré - Longueur Pied: 55.4 cm; Longueur Tête: 55.4 cm; Hauteur Maximale: 376.1 cm; Hauteur Minimale: 376.1 cm; Surface en Plan: 3000 cm2; Surface Pied: 3000 cm2; Surface Tête: 3000 cm2; Surface de la Paroi: 20800 cm2; Volume: 1140000 cm3
IFC_Pset_Matériaux - Face gauche: Ivoire clair; Face droite: Ivoire clair; Face latérale: Ivoire clair
Pset_WallCommon - Reference: default [547,00] (..\VERTICALES\Default\)
BaseQuantities - GrossVolume: 1139360 cm3; NetVolume: 1139360 cm3; NominalLength: 55.3819 cm; NominalWidth: 54.7 cm; NominalHeight: 376.102 cm; GrossFootprintArea: 3029.39 cm2; NetFootprintArea: 3029.39 cm2; GrossSideArea: 20829.2 cm2; NetSideArea: 20829.2 cm2

# IfcWallStandardCase: default 55 (4)
Type - Material: <aucun> 5.5 cm
Description: Enveloppe; Group: ...de stratigraphies = default; ...de matériaux et couleurs = Ivoire clair; ...de matériaux et couleurs - 1 = Ivoire clair; ...de matériaux et couleurs - 2 = Ivoire clair
__RECOGNIZE__ - TPLG: 366; TPLG_OD: 9000; GENERATE: 1
CTLG_EXTERNAL_LINK - 0, DocType: 2; 0, Tag: 0; 0, Crc: 1977773087; 1, DocType: 2; 1, Tag: 100; 1, Crc: 1977773087; 2, DocType: 2; 2, Tag: 200; 2, Crc: 1977773087; 3, DocType: 9; 3, Tag: 0; 3, Crc: 649754231
IFC_PSET_PolygonOffset - polygonOffsetFactor: 2; polygonOffsetUnits: 2
IFC_Pset_Caractéristiques - Stratigraphie: default [55,00]; Épaisseur: 5.5 cm; Épaisseur VARIABLE: no
IFC_Pset_Caractéristiques_FRUIT - Fruit: no; Taille: 0 cm
IFC_Pset_Géométrie - Forme en Élévation: rectangle
IFC_Pset_Système de Référence Altimétrique_SUPÉRIEUR - sous Niveau: <aucun>
IFC_Pset_Système de Référence Altimétrique_INFÉRIEUR - sous Niveau: <aucun>
IFC_Pset_Matériaux - Face gauche: Ivoire clair; Face droite: Ivoire clair; Face latérale: Ivoire clair
Pset_WallCommon - Reference: default [55,00] (..\VERTICALES\Default\)
BaseQuantities - NominalWidth: 5.5 cm
Name | In | __RECOGNIZE__, ID = IFC_Pset_Caractéristiques, ID | Alignment | ExternalFace | Numérotation | Numéro niveau | Titre niveau | Longueur (cm) = NominalLength (cm) | IFC_Pset_Géométrie, Hauteur (cm) = IFC_Pset_Géométrie_P1 (POINT initial), Hauteur (cm) = IFC_Pset_Géométrie_P2 (POINT final), Hauteur (cm) = NominalHeight (cm) | IFC_Pset_Géométrie, Cote (cm) = IFC_Pset_Géométrie_P1 (POINT initial), Cote (cm) = IFC_Pset_Géométrie_P2 (POINT final), Cote (cm) = IFC_Pset_Système de Référence Altimétrique_INFÉRIEUR, delta (cm) = IFC_Pset_Système de Référence Altimétrique_INFÉRIEUR, delta (P1) (cm) = IFC_Pset_Système de Référence Altimétrique_INFÉRIEUR, delta (P2) (cm) | IFC_Pset_Géométrie_P1 (POINT initial), Angle XY (deg) | IFC_Pset_Géométrie_P2 (POINT final), Angle XY (deg) | IFC_Pset_Système de Référence Altimétrique_SUPÉRIEUR, NIVEAU | IFC_Pset_Système de Référence Altimétrique_SUPÉRIEUR, delta (cm) = IFC_Pset_Système de Référence Altimétrique_SUPÉRIEUR, delta (P1) (cm) = IFC_Pset_Système de Référence Altimétrique_SUPÉRIEUR, delta (P2) (cm) | IFC_Pset_Système de Référence Altimétrique_INFÉRIEUR, NIVEAU | Longueur Pied (cm) = Longueur Tête (cm) | Hauteur Maximale (cm) = Hauteur Minimale (cm) | Surface en Plan (cm2) = Surface Pied (cm2) = Surface Tête (cm2) | Surface de la Paroi (cm2) | Volume (cm3) | GrossVolume (cm3) | NetVolume (cm3) | GrossFootprintArea (cm2) = NetFootprintArea (cm2) | GrossSideArea (cm2) | NetSideArea (cm2)
Enveloppe 67416 | Rez-de-Jardin | 67416 | 0 | 1 | 0125 | 02 | Rez-de-Jardin | 100.209 | 291.413 | -1.94511e-11 | 0.192193 | 180.192 | HAUT Rez-de-Jardin (Rez-de-chaussée 1047) | 0.0128504 | Rez-de-Jardin (Rez-de-Jardin 15545) | 100.2 | 291.4 | 600 | 29200 | 180000 | 160612 | 54864.5 | 551.147 | 29202.1 | 9975.36
Enveloppe 52922 | Rez-de-Jardin | 52922 | 1 | 0 | 0078 | 02 | Rez-de-Jardin | 136.931 | 291.413 | -1.94511e-11 | 90.2011 | 270.201 | HAUT Rez-de-Jardin (Rez-de-chaussée 1047) | 0.0128504 | Rez-de-Jardin (Rez-de-Jardin 15545) | 136.9 | 291.4 | 800 | 39900 | 240000 | 219470 | 129957 | 753.121 | 39903.5 | 23628.5
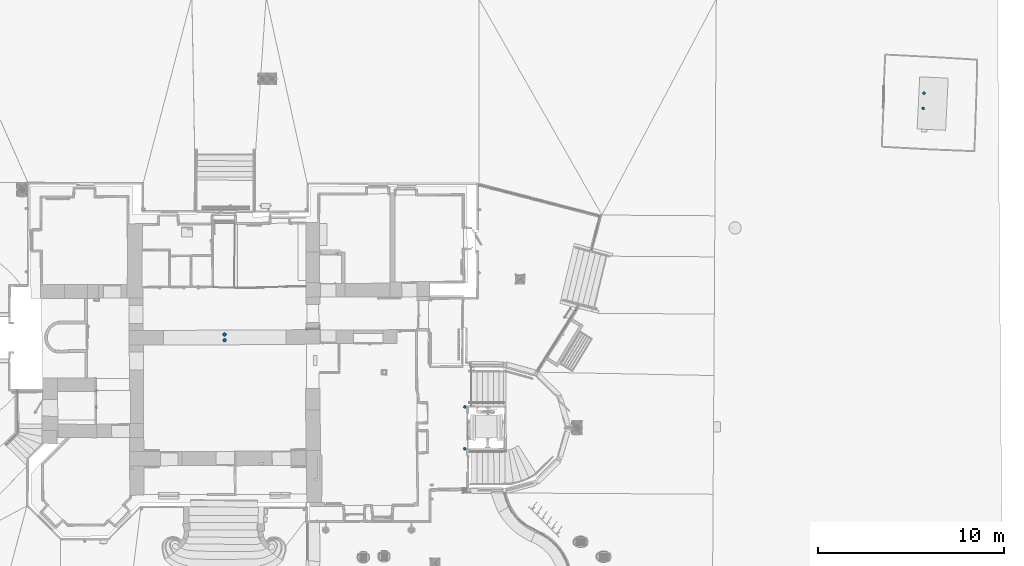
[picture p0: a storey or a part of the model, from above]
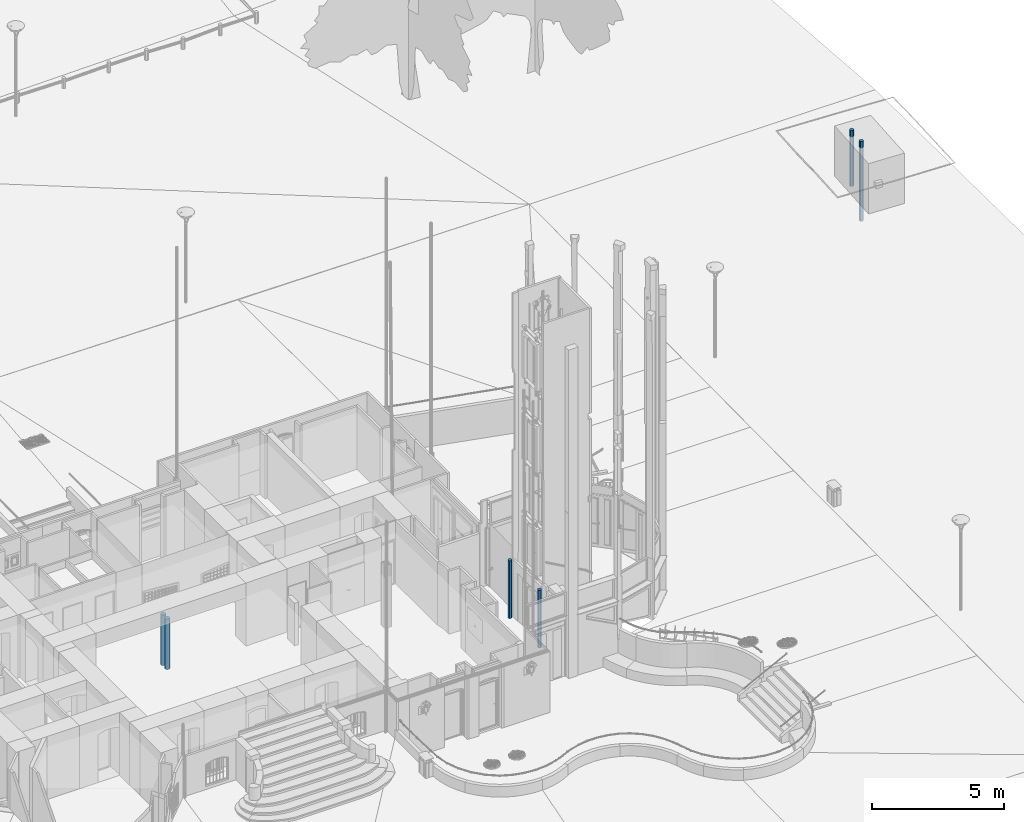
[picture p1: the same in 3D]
Properties of the parts of a building model (IFC2X3), part 25 of 37

# IfcWallStandardCase: default 55 (4)
Name | In | __RECOGNIZE__, ID = IFC_Pset_Caractéristiques, ID | Alignment | ExternalFace | Numérotation | Numéro niveau | Titre niveau | Longueur (cm) = NominalLength (cm) | IFC_Pset_Géométrie, Hauteur (cm) = IFC_Pset_Géométrie_P1 (POINT initial), Hauteur (cm) = IFC_Pset_Géométrie_P2 (POINT final), Hauteur (cm) = NominalHeight (cm) | IFC_Pset_Géométrie, Cote (cm) = IFC_Pset_Géométrie_P1 (POINT initial), Cote (cm) = IFC_Pset_Géométrie_P2 (POINT final), Cote (cm) = IFC_Pset_Système de Référence Altimétrique_INFÉRIEUR, delta (cm) = IFC_Pset_Système de Référence Altimétrique_INFÉRIEUR, delta (P1) (cm) = IFC_Pset_Système de Référence Altimétrique_INFÉRIEUR, delta (P2) (cm) | IFC_Pset_Géométrie_P1 (POINT initial), Angle XY (deg) | IFC_Pset_Géométrie_P2 (POINT final), Angle XY (deg) | IFC_Pset_Système de Référence Altimétrique_SUPÉRIEUR, NIVEAU | IFC_Pset_Système de Référence Altimétrique_SUPÉRIEUR, delta (cm) = IFC_Pset_Système de Référence Altimétrique_SUPÉRIEUR, delta (P1) (cm) = IFC_Pset_Système de Référence Altimétrique_SUPÉRIEUR, delta (P2) (cm) | IFC_Pset_Système de Référence Altimétrique_INFÉRIEUR, NIVEAU | Longueur Pied (cm) = Longueur Tête (cm) | Hauteur Maximale (cm) = Hauteur Minimale (cm) | Surface en Plan (cm2) = Surface Pied (cm2) = Surface Tête (cm2) | Surface de la Paroi (cm2) | Volume (cm3) | GrossVolume (cm3) | NetVolume (cm3) | GrossFootprintArea (cm2) = NetFootprintArea (cm2) | GrossSideArea (cm2) | NetSideArea (cm2)
Enveloppe 170790 | Niveau 2 | 170790 | 0 | 0 | 0424 | 05 | Niveau 2 | 26.9083 | 225 | 1.42109e-12 | 179.822 | 359.822 | HAUT Niveau 2 (Mezzanine 49003) | -10 | Niveau 2 (Niveau 2 13545) | 26.9 | 225 | 200 | 6100 | 40000 | 33299.1 | 33299.1 | 147.996 | 6054.37 | 6054.37
Enveloppe 170663 | Niveau 2 | 170663 | 1 | 0 | 0423 | 05 | Niveau 2 | 316.43 | 225 | 1.42109e-12 | 1.0252 | 181.025 | HAUT Niveau 2 (Mezzanine 49003) | -10 | Niveau 2 (Niveau 2 13545) | 316.4 | 225 | 1900 | 71200 | 430000 | 391582 | 391582 | 1740.37 | 71196.8 | 71196.8

# IfcWallStandardCase: default 550 (3)
Type - Material: <aucun> 55 cm
Description: Enveloppe; Group: ...de stratigraphies = default; ...de matériaux et couleurs = Ivoire clair; ...de matériaux et couleurs - 1 = Ivoire clair; ...de matériaux et couleurs - 2 = Ivoire clair
__RECOGNIZE__ - TPLG: 366; TPLG_OD: 9000; GENERATE: 1
CTLG_EXTERNAL_LINK - 0, DocType: 2; 0, Tag: 0; 0, Crc: 1977773087; 1, DocType: 2; 1, Tag: 100; 1, Crc: 1977773087; 2, DocType: 2; 2, Tag: 200; 2, Crc: 1977773087; 3, DocType: 9; 3, Tag: 0; 3, Crc: 674999326
IFC_PSET_PolygonOffset - polygonOffsetFactor: 2; polygonOffsetUnits: 2
IFC_Pset_Alignment - Alignment: 0
IFC_Pset_Strat_Detail_Align - ExternalFace: 0
IFC_Pset_Caractéristiques - Stratigraphie: default [550,00]; Épaisseur: 55 cm; Épaisseur VARIABLE: no
IFC_Pset_Caractéristiques_FRUIT - Fruit: no; Taille: 0 cm
IFC_Pset_Géométrie - Forme en Élévation: rectangle
IFC_Pset_Système de Référence Altimétrique_SUPÉRIEUR - sous Niveau: <aucun>
IFC_Pset_Système de Référence Altimétrique_INFÉRIEUR - sous Niveau: <aucun>
IFC_Pset_Matériaux - Face gauche: Ivoire clair; Face droite: Ivoire clair; Face latérale: Ivoire clair
Pset_WallCommon - Reference: default [550,00] (..\VERTICALES\Default\)
BaseQuantities - NominalWidth: 55 cm
Name | In | __RECOGNIZE__, ID = IFC_Pset_Caractéristiques, ID | Numérotation | Numéro niveau | Titre niveau | Longueur (cm) = NominalLength (cm) | IFC_Pset_Géométrie, Hauteur (cm) = IFC_Pset_Géométrie_P1 (POINT initial), Hauteur (cm) = IFC_Pset_Géométrie_P2 (POINT final), Hauteur (cm) = NominalHeight (cm) | IFC_Pset_Géométrie, Cote (cm) = IFC_Pset_Géométrie_P1 (POINT initial), Cote (cm) = IFC_Pset_Géométrie_P2 (POINT final), Cote (cm) = IFC_Pset_Système de Référence Altimétrique_INFÉRIEUR, delta (cm) = IFC_Pset_Système de Référence Altimétrique_INFÉRIEUR, delta (P1) (cm) = IFC_Pset_Système de Référence Altimétrique_INFÉRIEUR, delta (P2) (cm) | IFC_Pset_Géométrie_P1 (POINT initial), Angle XY (deg) | IFC_Pset_Géométrie_P2 (POINT final), Angle XY (deg) | IFC_Pset_Système de Référence Altimétrique_SUPÉRIEUR, NIVEAU | IFC_Pset_Système de Référence Altimétrique_SUPÉRIEUR, delta (cm) = IFC_Pset_Système de Référence Altimétrique_SUPÉRIEUR, delta (P1) (cm) = IFC_Pset_Système de Référence Altimétrique_SUPÉRIEUR, delta (P2) (cm) | IFC_Pset_Système de Référence Altimétrique_INFÉRIEUR, NIVEAU | Longueur Pied (cm) = Longueur Tête (cm) | Hauteur Maximale (cm) = Hauteur Minimale (cm) | Surface en Plan (cm2) = Surface Pied (cm2) = Surface Tête (cm2) | Surface de la Paroi (cm2) | Volume (cm3) | GrossVolume (cm3) | NetVolume (cm3) | GrossFootprintArea (cm2) = NetFootprintArea (cm2) | GrossSideArea (cm2) | NetSideArea (cm2)
Enveloppe 28083 | Rez-de-chaussée | 28083 | 0057 | 03 | Rez-de-chaussée | 99.4772 | 132.708 | 265 | 0.201098 | 180.201 | HAUT Rez-de-chaussée (Niveau 1 2343) | -80.0871 | Rez-de-chaussée (Rez-de-chaussée 1047) | 99.5 | 132.7 | 5500 | 13200 | 730000 | 726079 | 726079 | 5471.24 | 13201.4 | 13201.4
Enveloppe 119942 | Niveau 1 | 119942 | 0290 | 04 | Niveau 1 | 38.7561 | 376.102 | 0.0128504 | 90.174 | 270.174 | HAUT Niveau 1 (Niveau 2 13545) | 0 | Niveau 1 (Niveau 1 2343) | 38.8 | 376.1 | 2100 | 14600 | 800000 | 801693 | 801693 | 2131.58 | 14576.2 | 14576.2
Enveloppe 94087 | Niveau 1 | 94087 | 0222 | 04 | Niveau 1 | 327.772 | 376.102 | 0.0128504 | 90.1529 | 270.153 | HAUT Niveau 1 (Niveau 2 13545) | 0 | Niveau 1 (Niveau 1 2343) | 327.8 | 376.1 | 18000 | 123300 | 6780000 | 6780168 | 5874381 | 18027.5 | 123276 | 106807

# IfcWallStandardCase: default 551.057006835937, Enveloppe 2729
In: Rez-de-chaussée
Type - Material: <aucun> 55.1057 cm
Description: Enveloppe; Group: ...de stratigraphies = default; ...de matériaux et couleurs = Ivoire clair; ...de matériaux et couleurs - 1 = Ivoire clair; ...de matériaux et couleurs - 2 = Ivoire clair
__RECOGNIZE__ - ID: 2729; TPLG: 366; TPLG_OD: 9000; GENERATE: 1
CTLG_EXTERNAL_LINK - 0, DocType: 2; 0, Tag: 0; 0, Crc: 1977773087; 1, DocType: 2; 1, Tag: 100; 1, Crc: 1977773087; 2, DocType: 2; 2, Tag: 200; 2, Crc: 1977773087; 3, DocType: 9; 3, Tag: 0; 3, Crc: 324188809
IFC_PSET_PolygonOffset - polygonOffsetFactor: 2; polygonOffsetUnits: 2
IFC_Pset_Alignment - Alignment: 1
IFC_Pset_Strat_Detail_Align - ExternalFace: 0
IFC_Pset_Caractéristiques - ID: 2729; Numérotation: 0009; Numéro niveau: 03; Titre niveau: Rez-de-chaussée; Stratigraphie: default [551,06]; Épaisseur: 55.11 cm; Épaisseur VARIABLE: no
IFC_Pset_Caractéristiques_FRUIT - Fruit: no; Taille: 0 cm
IFC_Pset_Géométrie - Forme en Élévation: rectangle; Longueur: 593.595 cm; Hauteur: 395.995 cm; Cote: 0.0128504 cm
IFC_Pset_Géométrie_P1 (POINT initial) - Hauteur: 395.995 cm; Cote: 0.0128504 cm; Angle XY: 0.201098 deg
IFC_Pset_Géométrie_P2 (POINT final) - Hauteur: 395.995 cm; Cote: 0.0128504 cm; Angle XY: 180.201 deg
IFC_Pset_Système de Référence Altimétrique_SUPÉRIEUR - NIVEAU: HAUT Rez-de-chaussée (Niveau 1 2343); delta: -81.7871 cm; delta (P1): -81.7871 cm; delta (P2): -81.7871 cm; sous Niveau: <aucun>
IFC_Pset_Système de Référence Altimétrique_INFÉRIEUR - NIVEAU: Rez-de-chaussée (Rez-de-chaussée 1047); delta: 0.0128504 cm; delta (P1): 0.0128504 cm; delta (P2): 0.0128504 cm; sous Niveau: <aucun>
IFC_Pset_Données Métré - Longueur Pied: 593.6 cm; Longueur Tête: 593.6 cm; Hauteur Maximale: 396 cm; Hauteur Minimale: 396 cm; Surface en Plan: 32600 cm2; Surface Pied: 32600 cm2; Surface Tête: 32600 cm2; Surface de la Paroi: 235100 cm2; Volume: 12930000 cm3
IFC_Pset_Matériaux - Face gauche: Ivoire clair; Face droite: Ivoire clair; Face latérale: Ivoire clair
Pset_WallCommon - Reference: default [551,06] (..\VERTICALES\Default\)
BaseQuantities - GrossVolume: 12953203 cm3; NetVolume: 10950997 cm3; NominalLength: 593.595 cm; NominalWidth: 55.1057 cm; NominalHeight: 395.995 cm; GrossFootprintArea: 32710.5 cm2; NetFootprintArea: 32710.5 cm2; GrossSideArea: 235061 cm2; NetSideArea: 198727 cm2

# IfcWallStandardCase: default 552.076599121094 (5)
In: Rez-de-chaussée
Type - Material: <aucun> 55.2077 cm
Description: Enveloppe; Group: ...de stratigraphies = default; ...de matériaux et couleurs = Ivoire clair; ...de matériaux et couleurs - 1 = Ivoire clair; ...de matériaux et couleurs - 2 = Ivoire clair
__RECOGNIZE__ - TPLG: 366; TPLG_OD: 9000; GENERATE: 1
CTLG_EXTERNAL_LINK - 0, DocType: 2; 0, Tag: 0; 0, Crc: 1977773087; 1, DocType: 2; 1, Tag: 100; 1, Crc: 1977773087; 2, DocType: 2; 2, Tag: 200; 2, Crc: 1977773087; 3, DocType: 9; 3, Tag: 0; 3, Crc: -311984717
IFC_PSET_PolygonOffset - polygonOffsetFactor: 2; polygonOffsetUnits: 2
IFC_Pset_Alignment - Alignment: 0
IFC_Pset_Strat_Detail_Align - ExternalFace: 0
IFC_Pset_Caractéristiques - Numéro niveau: 03; Titre niveau: Rez-de-chaussée; Stratigraphie: default [552,08]; Épaisseur: 55.21 cm
IFC_Pset_Caractéristiques_FRUIT - Fruit: no; Taille: 0 cm
IFC_Pset_Géométrie - Forme en Élévation: rectangle
IFC_Pset_Système de Référence Altimétrique_SUPÉRIEUR - NIVEAU: HAUT Rez-de-chaussée (Niveau 1 2343); sous Niveau: <aucun>
IFC_Pset_Système de Référence Altimétrique_INFÉRIEUR - NIVEAU: Rez-de-chaussée (Rez-de-chaussée 1047); sous Niveau: <aucun>
IFC_Pset_Matériaux - Face gauche: Ivoire clair; Face droite: Ivoire clair; Face latérale: Ivoire clair
Pset_WallCommon - Reference: default [552,08] (..\VERTICALES\Default\)
Name | __RECOGNIZE__, ID = IFC_Pset_Caractéristiques, ID | Numérotation | Épaisseur VARIABLE | Longueur (cm) = NominalLength (cm) | IFC_Pset_Géométrie, Hauteur (cm) = IFC_Pset_Géométrie_P1 (POINT initial), Hauteur (cm) = IFC_Pset_Géométrie_P2 (POINT final), Hauteur (cm) = NominalHeight (cm) | IFC_Pset_Géométrie, Cote (cm) = IFC_Pset_Géométrie_P1 (POINT initial), Cote (cm) = IFC_Pset_Géométrie_P2 (POINT final), Cote (cm) = IFC_Pset_Système de Référence Altimétrique_INFÉRIEUR, delta (cm) = IFC_Pset_Système de Référence Altimétrique_INFÉRIEUR, delta (P1) (cm) = IFC_Pset_Système de Référence Altimétrique_INFÉRIEUR, delta (P2) (cm) | IFC_Pset_Géométrie_P1 (POINT initial), Angle XY (deg) | IFC_Pset_Géométrie_P2 (POINT final), Angle XY (deg) | IFC_Pset_Système de Référence Altimétrique_SUPÉRIEUR, delta (cm) = IFC_Pset_Système de Référence Altimétrique_SUPÉRIEUR, delta (P1) (cm) = IFC_Pset_Système de Référence Altimétrique_SUPÉRIEUR, delta (P2) (cm) | Longueur Pied (cm) = Longueur Tête (cm) | Hauteur Maximale (cm) = Hauteur Minimale (cm) | Surface en Plan (cm2) = Surface Pied (cm2) = Surface Tête (cm2) | Surface de la Paroi (cm2) | Volume (cm3) | GrossVolume (cm3) = NetVolume (cm3) | NominalWidth (cm) | GrossFootprintArea (cm2) = NetFootprintArea (cm2) | GrossSideArea (cm2) = NetSideArea (cm2)
Enveloppe 10853 | 10853 | 0049 | no | 273.136 | 63.4082 | 330 | 90.2846 | 270.285 | -84.3871 | 273.1 | 63.4 | 15000 | 17300 | 950000 | 956150 | 55.208 | 15079.3 | 17319
Enveloppe 30047 | 30047 | 0060 | yes | 62.2941 | 380.695 | 0.0128504 | 90.3156 | 270.316 | -97.0871 | 62.3 | 380.7 | 3500 | 23700 | 1330000 | 1318588 | 55.6012 | 3463.63 | 23715.1
Enveloppe 30314 | 30314 | 0061 | yes | 128.948 | 115.708 | 265 | 90.3156 | 270.316 | -97.0871 | 128.9 | 115.7 | 7100 | 14900 | 820000 | 826708 | 55.4081 | 7144.76 | 14920.3
Enveloppe 2767 | 2767 | 0011 | yes | 31.2755 | 380.695 | 0.0128504 | 90.3156 | 270.316 | -97.0871 | 31.3 | 380.7 | 1700 | 11900 | 660000 | 657792 | 55.2467 | 1727.87 | 11906.5
Enveloppe 2907 | 2907 | 0014 | yes | 221.919 | 382.495 | 0.0128504 | 90.174 | 270.174 | -95.2871 | 221.9 | 382.5 | 12400 | 84900 | 4750000 | 4745123 | 55.9018 | 12405.7 | 84883.2

# IfcWallStandardCase: default 556, Enveloppe 25234
In: Rez-de-chaussée
Type - Material: <aucun> 55.6 cm
Description: Enveloppe; Group: ...de stratigraphies = default; ...de matériaux et couleurs = Ivoire clair; ...de matériaux et couleurs - 1 = Ivoire clair; ...de matériaux et couleurs - 2 = Ivoire clair
__RECOGNIZE__ - ID: 25234; TPLG: 366; TPLG_OD: 9000; GENERATE: 1
CTLG_EXTERNAL_LINK - 0, DocType: 2; 0, Tag: 0; 0, Crc: 1977773087; 1, DocType: 2; 1, Tag: 100; 1, Crc: 1977773087; 2, DocType: 2; 2, Tag: 200; 2, Crc: 1977773087; 3, DocType: 9; 3, Tag: 0; 3, Crc: -1394158776
IFC_PSET_PolygonOffset - polygonOffsetFactor: 2; polygonOffsetUnits: 2
IFC_Pset_Alignment - Alignment: 1
IFC_Pset_Strat_Detail_Align - ExternalFace: 0
IFC_Pset_Caractéristiques - ID: 25234; Numérotation: 0055; Numéro niveau: 03; Titre niveau: Rez-de-chaussée; Stratigraphie: default [556,00]; Épaisseur: 55.6 cm; Épaisseur VARIABLE: yes
IFC_Pset_Caractéristiques_FRUIT - Fruit: no; Taille: 0 cm
IFC_Pset_Géométrie - Forme en Élévation: rectangle; Longueur: 88.5131 cm; Hauteur: 399.097 cm; Cote: 0.0128504 cm
IFC_Pset_Géométrie_P1 (POINT initial) - Hauteur: 399.097 cm; Cote: 0.0128504 cm; Angle XY: 90.4996 deg
IFC_Pset_Géométrie_P2 (POINT final) - Hauteur: 399.097 cm; Cote: 0.0128504 cm; Angle XY: 270.5 deg
IFC_Pset_Système de Référence Altimétrique_SUPÉRIEUR - NIVEAU: HAUT Rez-de-chaussée (Niveau 1 2343); delta: -78.6853 cm; delta (P1): -78.6853 cm; delta (P2): -78.6853 cm; sous Niveau: <aucun>
IFC_Pset_Système de Référence Altimétrique_INFÉRIEUR - NIVEAU: Rez-de-chaussée (Rez-de-chaussée 1047); delta: 0.0128504 cm; delta (P1): 0.0128504 cm; delta (P2): 0.0128504 cm; sous Niveau: <aucun>
IFC_Pset_Données Métré - Longueur Pied: 88.5 cm; Longueur Tête: 88.5 cm; Hauteur Maximale: 399.1 cm; Hauteur Minimale: 399.1 cm; Surface en Plan: 5000 cm2; Surface Pied: 5000 cm2; Surface Tête: 5000 cm2; Surface de la Paroi: 35300 cm2; Volume: 1980000 cm3
IFC_Pset_Matériaux - Face gauche: Ivoire clair; Face droite: Ivoire clair; Face latérale: Ivoire clair
Pset_WallCommon - Reference: default [556,00] (..\VERTICALES\Default\)
BaseQuantities - GrossVolume: 1994099 cm3; NetVolume: 1994099 cm3; NominalLength: 88.5131 cm; NominalWidth: 56.4496 cm; NominalHeight: 399.097 cm; GrossFootprintArea: 4996.53 cm2; NetFootprintArea: 4996.53 cm2; GrossSideArea: 35325.3 cm2; NetSideArea: 35325.3 cm2

# IfcWallStandardCase: default 558.431457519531, Enveloppe 2756
In: Rez-de-chaussée
Type - Material: <aucun> 55.8431 cm
Description: Enveloppe; Group: ...de stratigraphies = default; ...de matériaux et couleurs = Ivoire clair; ...de matériaux et couleurs - 1 = Ivoire clair; ...de matériaux et couleurs - 2 = Ivoire clair
__RECOGNIZE__ - ID: 2756; TPLG: 366; TPLG_OD: 9000; GENERATE: 1
CTLG_EXTERNAL_LINK - 0, DocType: 2; 0, Tag: 0; 0, Crc: 1977773087; 1, DocType: 2; 1, Tag: 100; 1, Crc: 1977773087; 2, DocType: 2; 2, Tag: 200; 2, Crc: 1977773087; 3, DocType: 9; 3, Tag: 0; 3, Crc: 1434892249
IFC_PSET_PolygonOffset - polygonOffsetFactor: 2; polygonOffsetUnits: 2
IFC_Pset_Alignment - Alignment: 0
IFC_Pset_Strat_Detail_Align - ExternalFace: 1
IFC_Pset_Caractéristiques - ID: 2756; Numérotation: 0010; Numéro niveau: 03; Titre niveau: Rez-de-chaussée; Stratigraphie: default [558,43]; Épaisseur: 55.84 cm; Épaisseur VARIABLE: no
IFC_Pset_Caractéristiques_FRUIT - Fruit: no; Taille: 0 cm
IFC_Pset_Géométrie - Forme en Élévation: rectangle; Longueur: 895.04 cm; Hauteur: 382.495 cm; Cote: 0.0128504 cm
IFC_Pset_Géométrie_P1 (POINT initial) - Hauteur: 382.495 cm; Cote: 0.0128504 cm; Angle XY: 0.303763 deg
IFC_Pset_Géométrie_P2 (POINT final) - Hauteur: 382.495 cm; Cote: 0.0128504 cm; Angle XY: 180.304 deg
IFC_Pset_Système de Référence Altimétrique_SUPÉRIEUR - NIVEAU: HAUT Rez-de-chaussée (Niveau 1 2343); delta: -95.2871 cm; delta (P1): -95.2871 cm; delta (P2): -95.2871 cm; sous Niveau: <aucun>
IFC_Pset_Système de Référence Altimétrique_INFÉRIEUR - NIVEAU: Rez-de-chaussée (Rez-de-chaussée 1047); delta: 0.0128504 cm; delta (P1): 0.0128504 cm; delta (P2): 0.0128504 cm; sous Niveau: <aucun>
IFC_Pset_Données Métré - Longueur Pied: 895 cm; Longueur Tête: 895 cm; Hauteur Maximale: 382.5 cm; Hauteur Minimale: 382.5 cm; Surface en Plan: 50100 cm2; Surface Pied: 50100 cm2; Surface Tête: 50100 cm2; Surface de la Paroi: 342300 cm2; Volume: 19170000 cm3
IFC_Pset_Matériaux - Face gauche: Ivoire clair; Face droite: Ivoire clair; Face latérale: Ivoire clair
Pset_WallCommon - Reference: default [558,43] (..\VERTICALES\Default\)
BaseQuantities - GrossVolume: 19117826 cm3; NetVolume: 13239834 cm3; NominalLength: 895.04 cm; NominalWidth: 55.8431 cm; NominalHeight: 382.495 cm; GrossFootprintArea: 49981.9 cm2; NetFootprintArea: 49981.9 cm2; GrossSideArea: 342349 cm2; NetSideArea: 237090 cm2

# IfcWallStandardCase: default 560 (2)
In: Niveau 1
Type - Material: <aucun> 56 cm
Description: Enveloppe; Group: ...de stratigraphies = default; ...de matériaux et couleurs = Ivoire clair; ...de matériaux et couleurs - 1 = Ivoire clair; ...de matériaux et couleurs - 2 = Ivoire clair
__RECOGNIZE__ - TPLG: 366; TPLG_OD: 9000; GENERATE: 1
CTLG_EXTERNAL_LINK - 0, DocType: 2; 0, Tag: 0; 0, Crc: 1977773087; 1, DocType: 2; 1, Tag: 100; 1, Crc: 1977773087; 2, DocType: 2; 2, Tag: 200; 2, Crc: 1977773087; 3, DocType: 9; 3, Tag: 0; 3, Crc: -2029589201
IFC_PSET_PolygonOffset - polygonOffsetFactor: 2; polygonOffsetUnits: 2
IFC_Pset_Strat_Detail_Align - ExternalFace: 0
IFC_Pset_Caractéristiques - Numéro niveau: 04; Titre niveau: Niveau 1; Stratigraphie: default [560,00]; Épaisseur: 56 cm
IFC_Pset_Caractéristiques_FRUIT - Fruit: no; Taille: 0 cm
IFC_Pset_Géométrie - Forme en Élévation: rectangle; Hauteur: 376.102 cm; Cote: 0.0128504 cm
IFC_Pset_Géométrie_P1 (POINT initial) - Hauteur: 376.102 cm; Cote: 0.0128504 cm
IFC_Pset_Géométrie_P2 (POINT final) - Hauteur: 376.102 cm; Cote: 0.0128504 cm
IFC_Pset_Système de Référence Altimétrique_SUPÉRIEUR - NIVEAU: HAUT Niveau 1 (Niveau 2 13545); delta: 0 cm; delta (P1): 0 cm; delta (P2): 0 cm; sous Niveau: <aucun>
IFC_Pset_Système de Référence Altimétrique_INFÉRIEUR - NIVEAU: Niveau 1 (Niveau 1 2343); delta: 0.0128504 cm; delta (P1): 0.0128504 cm; delta (P2): 0.0128504 cm; sous Niveau: <aucun>
IFC_Pset_Données Métré - Hauteur Maximale: 376.1 cm; Hauteur Minimale: 376.1 cm
IFC_Pset_Matériaux - Face gauche: Ivoire clair; Face droite: Ivoire clair; Face latérale: Ivoire clair
Pset_WallCommon - Reference: default [560,00] (..\VERTICALES\Default\)
BaseQuantities - NominalHeight: 376.102 cm
Name | __RECOGNIZE__, ID = IFC_Pset_Caractéristiques, ID | Alignment | Numérotation | Épaisseur VARIABLE | Longueur (cm) = NominalLength (cm) | IFC_Pset_Géométrie_P1 (POINT initial), Angle XY (deg) | IFC_Pset_Géométrie_P2 (POINT final), Angle XY (deg) | Longueur Pied (cm) = Longueur Tête (cm) | Surface en Plan (cm2) = Surface Pied (cm2) = Surface Tête (cm2) | Surface de la Paroi (cm2) | Volume (cm3) | GrossVolume (cm3) | NetVolume (cm3) | NominalWidth (cm) | GrossFootprintArea (cm2) = NetFootprintArea (cm2) | GrossSideArea (cm2) | NetSideArea (cm2)
Enveloppe 92847 | 92847 | 0 | 0195 | no | 224.787 | 90.3156 | 270.316 | 224.8 | 12600 | 84500 | 4730000 | 4734396 | 2820592 | 56 | 12588.1 | 84542.8 | 50367.7
Enveloppe 119135 | 119135 | 1 | 0286 | yes | 21.1736 | 90.3835 | 270.384 | 21.2 | 1200 | 8000 | 450000 | 451230 | 451230 | 56.6626 | 1199.75 | 7963.45 | 7963.45

# IfcWallStandardCase: default 564 (2)
In: Rez-de-chaussée
Type - Material: <aucun> 56.4 cm
Description: Enveloppe; Group: ...de stratigraphies = default; ...de matériaux et couleurs = Ivoire clair; ...de matériaux et couleurs - 1 = Ivoire clair; ...de matériaux et couleurs - 2 = Ivoire clair
__RECOGNIZE__ - TPLG: 366; TPLG_OD: 9000; GENERATE: 1
CTLG_EXTERNAL_LINK - 0, DocType: 2; 0, Tag: 0; 0, Crc: 1977773087; 1, DocType: 2; 1, Tag: 100; 1, Crc: 1977773087; 2, DocType: 2; 2, Tag: 200; 2, Crc: 1977773087; 3, DocType: 9; 3, Tag: 0; 3, Crc: -636055766
IFC_PSET_PolygonOffset - polygonOffsetFactor: 2; polygonOffsetUnits: 2
IFC_Pset_Alignment - Alignment: 1
IFC_Pset_Strat_Detail_Align - ExternalFace: 0
IFC_Pset_Caractéristiques - Numéro niveau: 03; Titre niveau: Rez-de-chaussée; Stratigraphie: default [564,00]; Épaisseur: 56.4 cm; Épaisseur VARIABLE: no
IFC_Pset_Caractéristiques_FRUIT - Fruit: no; Taille: 0 cm
IFC_Pset_Géométrie - Forme en Élévation: rectangle; Cote: 0.0128504 cm
IFC_Pset_Géométrie_P1 (POINT initial) - Cote: 0.0128504 cm; Angle XY: 90.1529 deg
IFC_Pset_Géométrie_P2 (POINT final) - Cote: 0.0128504 cm; Angle XY: 270.153 deg
IFC_Pset_Système de Référence Altimétrique_SUPÉRIEUR - NIVEAU: HAUT Rez-de-chaussée (Niveau 1 2343); sous Niveau: <aucun>
IFC_Pset_Système de Référence Altimétrique_INFÉRIEUR - NIVEAU: Rez-de-chaussée (Rez-de-chaussée 1047); delta: 0.0128504 cm; delta (P1): 0.0128504 cm; delta (P2): 0.0128504 cm; sous Niveau: <aucun>
IFC_Pset_Matériaux - Face gauche: Ivoire clair; Face droite: Ivoire clair; Face latérale: Ivoire clair
Pset_WallCommon - Reference: default [564,00] (..\VERTICALES\Default\)
BaseQuantities - NominalWidth: 56.4 cm
Name | __RECOGNIZE__, ID = IFC_Pset_Caractéristiques, ID | Numérotation | Longueur (cm) = NominalLength (cm) | IFC_Pset_Géométrie, Hauteur (cm) = IFC_Pset_Géométrie_P1 (POINT initial), Hauteur (cm) = IFC_Pset_Géométrie_P2 (POINT final), Hauteur (cm) = NominalHeight (cm) | delta (cm) = delta (P1) (cm) = delta (P2) (cm) | Longueur Pied (cm) = Longueur Tête (cm) | Hauteur Maximale (cm) = Hauteur Minimale (cm) | Surface en Plan (cm2) = Surface Pied (cm2) = Surface Tête (cm2) | Surface de la Paroi (cm2) | Volume (cm3) | GrossVolume (cm3) | NetVolume (cm3) | GrossFootprintArea (cm2) = NetFootprintArea (cm2) | GrossSideArea (cm2) | NetSideArea (cm2)
Enveloppe 2878 | 2878 | 0013 | 200.611 | 399.097 | -78.6853 | 200.6 | 399.1 | 11200 | 80100 | 4490000 | 4515575 | 3401614 | 11314.5 | 80063.4 | 60312.3
Enveloppe 2996 | 2996 | 0016 | 404.62 | 382.495 | -95.2871 | 404.6 | 382.5 | 22600 | 154800 | 8670000 | 8728754 | 6781285 | 22820.6 | 154765 | 120236

# IfcWallStandardCase: default 565, Enveloppe 94064
In: Niveau 1
Type - Material: <aucun> 56.5 cm
Description: Enveloppe; Group: ...de stratigraphies = default; ...de matériaux et couleurs = Ivoire clair; ...de matériaux et couleurs - 1 = Ivoire clair; ...de matériaux et couleurs - 2 = Ivoire clair
__RECOGNIZE__ - ID: 94064; TPLG: 366; TPLG_OD: 9000; GENERATE: 1
CTLG_EXTERNAL_LINK - 0, DocType: 2; 0, Tag: 0; 0, Crc: 1977773087; 1, DocType: 2; 1, Tag: 100; 1, Crc: 1977773087; 2, DocType: 2; 2, Tag: 200; 2, Crc: 1977773087; 3, DocType: 9; 3, Tag: 0; 3, Crc: -847145929
IFC_PSET_PolygonOffset - polygonOffsetFactor: 2; polygonOffsetUnits: 2
IFC_Pset_Alignment - Alignment: 1
IFC_Pset_Strat_Detail_Align - ExternalFace: 0
IFC_Pset_Caractéristiques - ID: 94064; Numérotation: 0221; Numéro niveau: 04; Titre niveau: Niveau 1; Stratigraphie: default [565,00]; Épaisseur: 56.5 cm; Épaisseur VARIABLE: yes
IFC_Pset_Caractéristiques_FRUIT - Fruit: no; Taille: 0 cm
IFC_Pset_Géométrie - Forme en Élévation: rectangle; Longueur: 41.6754 cm; Hauteur: 376.102 cm; Cote: 0.0128504 cm
IFC_Pset_Géométrie_P1 (POINT initial) - Hauteur: 376.102 cm; Cote: 0.0128504 cm; Angle XY: 90.3835 deg
IFC_Pset_Géométrie_P2 (POINT final) - Hauteur: 376.102 cm; Cote: 0.0128504 cm; Angle XY: 270.384 deg
IFC_Pset_Système de Référence Altimétrique_SUPÉRIEUR - NIVEAU: HAUT Niveau 1 (Niveau 2 13545); delta: 0 cm; delta (P1): 0 cm; delta (P2): 0 cm; sous Niveau: <aucun>
IFC_Pset_Système de Référence Altimétrique_INFÉRIEUR - NIVEAU: Niveau 1 (Niveau 1 2343); delta: 0.0128504 cm; delta (P1): 0.0128504 cm; delta (P2): 0.0128504 cm; sous Niveau: <aucun>
IFC_Pset_Données Métré - Longueur Pied: 41.7 cm; Longueur Tête: 41.7 cm; Hauteur Maximale: 376.1 cm; Hauteur Minimale: 376.1 cm; Surface en Plan: 2400 cm2; Surface Pied: 2400 cm2; Surface Tête: 2400 cm2; Surface de la Paroi: 15700 cm2; Volume: 890000 cm3
IFC_Pset_Matériaux - Face gauche: Ivoire clair; Face droite: Ivoire clair; Face latérale: Ivoire clair
Pset_WallCommon - Reference: default [565,00] (..\VERTICALES\Default\)
BaseQuantities - GrossVolume: 887147 cm3; NetVolume: 887147 cm3; NominalLength: 41.6754 cm; NominalWidth: 56.5992 cm; NominalHeight: 376.102 cm; GrossFootprintArea: 2358.79 cm2; NetFootprintArea: 2358.79 cm2; GrossSideArea: 15674.2 cm2; NetSideArea: 15674.2 cm2

# IfcWallStandardCase: default 57 (2)
In: Niveau 2
Type - Material: <aucun> 5.7 cm
Description: Enveloppe; Group: ...de stratigraphies = default; ...de matériaux et couleurs = Ivoire clair; ...de matériaux et couleurs - 1 = Ivoire clair; ...de matériaux et couleurs - 2 = Ivoire clair
__RECOGNIZE__ - TPLG: 366; TPLG_OD: 9000; GENERATE: 1
CTLG_EXTERNAL_LINK - 0, DocType: 2; 0, Tag: 0; 0, Crc: 1977773087; 1, DocType: 2; 1, Tag: 100; 1, Crc: 1977773087; 2, DocType: 2; 2, Tag: 200; 2, Crc: 1977773087; 3, DocType: 9; 3, Tag: 0; 3, Crc: -1464960946
IFC_PSET_PolygonOffset - polygonOffsetFactor: 2; polygonOffsetUnits: 2
IFC_Pset_Strat_Detail_Align - ExternalFace: 0
IFC_Pset_Caractéristiques - Numéro niveau: 05; Titre niveau: Niveau 2; Stratigraphie: default [57,00]; Épaisseur: 5.7 cm; Épaisseur VARIABLE: no
IFC_Pset_Caractéristiques_FRUIT - Fruit: no; Taille: 0 cm
IFC_Pset_Géométrie - Forme en Élévation: rectangle; Hauteur: 225 cm; Cote: 1.42109e-12 cm
IFC_Pset_Géométrie_P1 (POINT initial) - Hauteur: 225 cm; Cote: 1.42109e-12 cm
IFC_Pset_Géométrie_P2 (POINT final) - Hauteur: 225 cm; Cote: 1.42109e-12 cm
IFC_Pset_Système de Référence Altimétrique_SUPÉRIEUR - NIVEAU: HAUT Niveau 2 (Mezzanine 49003); delta: -10 cm; delta (P1): -10 cm; delta (P2): -10 cm; sous Niveau: <aucun>
IFC_Pset_Système de Référence Altimétrique_INFÉRIEUR - NIVEAU: Niveau 2 (Niveau 2 13545); delta: 1.42109e-12 cm; delta (P1): 1.42109e-12 cm; delta (P2): 1.42109e-12 cm; sous Niveau: <aucun>
IFC_Pset_Données Métré - Longueur Pied: 80.2 cm; Longueur Tête: 80.2 cm; Hauteur Maximale: 225 cm; Hauteur Minimale: 225 cm; Surface en Plan: 500 cm2; Surface Pied: 500 cm2; Surface Tête: 500 cm2; Surface de la Paroi: 18000 cm2; Volume: 110000 cm3
IFC_Pset_Matériaux - Face gauche: Ivoire clair; Face droite: Ivoire clair; Face latérale: Ivoire clair
Pset_WallCommon - Reference: default [57,00] (..\VERTICALES\Default\)
BaseQuantities - NominalWidth: 5.7 cm; NominalHeight: 225 cm
Name | __RECOGNIZE__, ID = IFC_Pset_Caractéristiques, ID | Alignment | Numérotation | Longueur (cm) = NominalLength (cm) | IFC_Pset_Géométrie_P1 (POINT initial), Angle XY (deg) | IFC_Pset_Géométrie_P2 (POINT final), Angle XY (deg) | GrossVolume (cm3) | NetVolume (cm3) | GrossFootprintArea (cm2) = NetFootprintArea (cm2) | GrossSideArea (cm2) | NetSideArea (cm2)
Enveloppe 151435 | 151435 | 0 | 0350 | 80.1704 | 179.747 | 359.747 | 102818 | 16393 | 456.971 | 18038.3 | 2875.96
Enveloppe 151102 | 151102 | 1 | 0348 | 80.2262 | 0.564788 | 180.565 | 102890 | 16393.8 | 457.29 | 18050.9 | 2876.1

# IfcWallStandardCase: default 57.4674491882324 (2)
In: Rez-de-chaussée
Type - Material: <aucun> 5.74674 cm
Description: Enveloppe; Group: ...de stratigraphies = default; ...de matériaux et couleurs = Ivoire clair; ...de matériaux et couleurs - 1 = Ivoire clair; ...de matériaux et couleurs - 2 = Ivoire clair
__RECOGNIZE__ - TPLG: 366; TPLG_OD: 9000; GENERATE: 1
CTLG_EXTERNAL_LINK - 0, DocType: 2; 0, Tag: 0; 0, Crc: 1977773087; 1, DocType: 2; 1, Tag: 100; 1, Crc: 1977773087; 2, DocType: 2; 2, Tag: 200; 2, Crc: 1977773087; 3, DocType: 9; 3, Tag: 0; 3, Crc: -1604330877
IFC_PSET_PolygonOffset - polygonOffsetFactor: 2; polygonOffsetUnits: 2
IFC_Pset_Strat_Detail_Align - ExternalFace: 0
IFC_Pset_Caractéristiques - Numéro niveau: 03; Titre niveau: Rez-de-chaussée; Stratigraphie: default [57,47]; Épaisseur: 5.75 cm; Épaisseur VARIABLE: no
IFC_Pset_Caractéristiques_FRUIT - Fruit: no; Taille: 0 cm
IFC_Pset_Géométrie - Forme en Élévation: rectangle; Hauteur: 391.395 cm; Cote: 0.0128504 cm
IFC_Pset_Géométrie_P1 (POINT initial) - Hauteur: 391.395 cm; Cote: 0.0128504 cm
IFC_Pset_Géométrie_P2 (POINT final) - Hauteur: 391.395 cm; Cote: 0.0128504 cm
IFC_Pset_Système de Référence Altimétrique_SUPÉRIEUR - NIVEAU: HAUT Rez-de-chaussée (Niveau 1 2343); delta: -86.3871 cm; delta (P1): -86.3871 cm; delta (P2): -86.3871 cm; sous Niveau: <aucun>
IFC_Pset_Système de Référence Altimétrique_INFÉRIEUR - NIVEAU: Rez-de-chaussée (Rez-de-chaussée 1047); delta: 0.0128504 cm; delta (P1): 0.0128504 cm; delta (P2): 0.0128504 cm; sous Niveau: <aucun>
IFC_Pset_Données Métré - Hauteur Maximale: 391.4 cm; Hauteur Minimale: 391.4 cm
IFC_Pset_Matériaux - Face gauche: Ivoire clair; Face droite: Ivoire clair; Face latérale: Ivoire clair
Pset_WallCommon - Reference: default [57,47] (..\VERTICALES\Default\)
BaseQuantities - NominalHeight: 391.395 cm
Name | __RECOGNIZE__, ID = IFC_Pset_Caractéristiques, ID | Alignment | Numérotation | Longueur (cm) = NominalLength (cm) | IFC_Pset_Géométrie_P1 (POINT initial), Angle XY (deg) | IFC_Pset_Géométrie_P2 (POINT final), Angle XY (deg) | Longueur Pied (cm) = Longueur Tête (cm) | Surface en Plan (cm2) = Surface Pied (cm2) = Surface Tête (cm2) | Surface de la Paroi (cm2) | Volume (cm3) | GrossVolume (cm3) = NetVolume (cm3) | NominalWidth (cm) | GrossFootprintArea (cm2) = NetFootprintArea (cm2) | GrossSideArea (cm2) = NetSideArea (cm2)
Enveloppe 3594 | 3594 | 0 | 0034 | 76.1088 | 179.377 | 359.377 | 76.1 | 500 | 29800 | 180000 | 171165 | 5.746 | 437.321 | 29788.6
Enveloppe 3523 | 3523 | 1 | 0033 | 312.858 | 0.0800045 | 180.08 | 312.8 | 1900 | 122400 | 730000 | 703696 | 5.74674 | 1797.91 | 122451

# IfcWallStandardCase: default 58.4991302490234 (2)
In: Rez-de-chaussée
Type - Material: <aucun> 5.84991 cm
Description: Enveloppe; Group: ...de stratigraphies = default; ...de matériaux et couleurs = Ivoire clair; ...de matériaux et couleurs - 1 = Ivoire clair; ...de matériaux et couleurs - 2 = Ivoire clair
__RECOGNIZE__ - TPLG: 366; TPLG_OD: 9000; GENERATE: 1
CTLG_EXTERNAL_LINK - 0, DocType: 2; 0, Tag: 0; 0, Crc: 1977773087; 1, DocType: 2; 1, Tag: 100; 1, Crc: 1977773087; 2, DocType: 2; 2, Tag: 200; 2, Crc: 1977773087; 3, DocType: 9; 3, Tag: 0; 3, Crc: 1274134659
IFC_PSET_PolygonOffset - polygonOffsetFactor: 2; polygonOffsetUnits: 2
IFC_Pset_Alignment - Alignment: 1
IFC_Pset_Strat_Detail_Align - ExternalFace: 0
IFC_Pset_Caractéristiques - Numéro niveau: 03; Titre niveau: Rez-de-chaussée; Stratigraphie: default [58,50]; Épaisseur: 5.85 cm; Épaisseur VARIABLE: no
IFC_Pset_Caractéristiques_FRUIT - Fruit: no; Taille: 0 cm
IFC_Pset_Géométrie - Forme en Élévation: rectangle; Cote: 0.0128504 cm
IFC_Pset_Géométrie_P1 (POINT initial) - Cote: 0.0128504 cm
IFC_Pset_Géométrie_P2 (POINT final) - Cote: 0.0128504 cm
IFC_Pset_Système de Référence Altimétrique_SUPÉRIEUR - NIVEAU: HAUT Rez-de-chaussée (Niveau 1 2343); sous Niveau: <aucun>
IFC_Pset_Système de Référence Altimétrique_INFÉRIEUR - NIVEAU: Rez-de-chaussée (Rez-de-chaussée 1047); delta: 0.0128504 cm; delta (P1): 0.0128504 cm; delta (P2): 0.0128504 cm; sous Niveau: <aucun>
IFC_Pset_Matériaux - Face gauche: Ivoire clair; Face droite: Ivoire clair; Face latérale: Ivoire clair
Pset_WallCommon - Reference: default [58,50] (..\VERTICALES\Default\)
BaseQuantities - NominalWidth: 5.84991 cm
Name | __RECOGNIZE__, ID = IFC_Pset_Caractéristiques, ID | Numérotation | Longueur (cm) = NominalLength (cm) | IFC_Pset_Géométrie, Hauteur (cm) = IFC_Pset_Géométrie_P1 (POINT initial), Hauteur (cm) = IFC_Pset_Géométrie_P2 (POINT final), Hauteur (cm) = NominalHeight (cm) | IFC_Pset_Géométrie_P1 (POINT initial), Angle XY (deg) | IFC_Pset_Géométrie_P2 (POINT final), Angle XY (deg) | delta (cm) = delta (P1) (cm) = delta (P2) (cm) | Longueur Pied (cm) = Longueur Tête (cm) | Hauteur Maximale (cm) = Hauteur Minimale (cm) | Surface en Plan (cm2) = Surface Pied (cm2) = Surface Tête (cm2) | Surface de la Paroi (cm2) | Volume (cm3) | GrossVolume (cm3) | NetVolume (cm3) | GrossFootprintArea (cm2) = NetFootprintArea (cm2) | GrossSideArea (cm2) | NetSideArea (cm2)
Enveloppe 11540 | 11540 | 0050 | 198.006 | 267.795 | 90.8845 | 270.884 | -209.987 | 198 | 267.8 | 1200 | 53000 | 320000 | 310192 | 310192 | 1158.32 | 53025.1 | 53025.1
Enveloppe 3504 | 3504 | 0032 | 225.589 | 205 | 0.0515293 | 180.052 | -272.783 | 225.6 | 205 | 1400 | 46200 | 280000 | 270534 | 99529.4 | 1319.68 | 46245.8 | 17013.8

# IfcWallStandardCase: default 585.635131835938 (2)
In: Niveau 2
Type - Material: <aucun> 58.5635 cm
Description: Enveloppe; Group: ...de stratigraphies = default; ...de matériaux et couleurs = Ivoire clair; ...de matériaux et couleurs - 1 = Ivoire clair; ...de matériaux et couleurs - 2 = Ivoire clair
__RECOGNIZE__ - TPLG: 366; TPLG_OD: 9000; GENERATE: 1
CTLG_EXTERNAL_LINK - 0, DocType: 2; 0, Tag: 0; 0, Crc: 1977773087; 1, DocType: 2; 1, Tag: 100; 1, Crc: 1977773087; 2, DocType: 2; 2, Tag: 200; 2, Crc: 1977773087; 3, DocType: 9; 3, Tag: 0; 3, Crc: 8064096
IFC_PSET_PolygonOffset - polygonOffsetFactor: 2; polygonOffsetUnits: 2
IFC_Pset_Alignment - Alignment: 1
IFC_Pset_Strat_Detail_Align - ExternalFace: 0
IFC_Pset_Caractéristiques - Numéro niveau: 05; Titre niveau: Niveau 2; Stratigraphie: default [585,64]; Épaisseur: 58.56 cm; Épaisseur VARIABLE: no
IFC_Pset_Caractéristiques_FRUIT - Fruit: no; Taille: 0 cm
IFC_Pset_Géométrie - Forme en Élévation: rectangle; Cote: 1.42109e-12 cm
IFC_Pset_Géométrie_P1 (POINT initial) - Cote: 1.42109e-12 cm; Angle XY: 0.0800045 deg
IFC_Pset_Géométrie_P2 (POINT final) - Cote: 1.42109e-12 cm; Angle XY: 180.08 deg
IFC_Pset_Système de Référence Altimétrique_SUPÉRIEUR - NIVEAU: HAUT Niveau 2 (Mezzanine 49003); sous Niveau: <aucun>
IFC_Pset_Système de Référence Altimétrique_INFÉRIEUR - NIVEAU: Niveau 2 (Niveau 2 13545); delta: 1.42109e-12 cm; delta (P1): 1.42109e-12 cm; delta (P2): 1.42109e-12 cm; sous Niveau: <aucun>
IFC_Pset_Matériaux - Face gauche: Ivoire clair; Face droite: Ivoire clair; Face latérale: Ivoire clair
Pset_WallCommon - Reference: default [585,64] (..\VERTICALES\Default\)
BaseQuantities - NominalWidth: 58.5635 cm
Name | __RECOGNIZE__, ID = IFC_Pset_Caractéristiques, ID | Numérotation | Longueur (cm) = NominalLength (cm) | IFC_Pset_Géométrie, Hauteur (cm) = IFC_Pset_Géométrie_P1 (POINT initial), Hauteur (cm) = IFC_Pset_Géométrie_P2 (POINT final), Hauteur (cm) = Hauteur Maximale (cm) = Hauteur Minimale (cm) = NominalHeight (cm) | delta (cm) = delta (P1) (cm) = delta (P2) (cm) | Longueur Pied (cm) = Longueur Tête (cm) | Surface en Plan (cm2) = Surface Pied (cm2) = Surface Tête (cm2) | Surface de la Paroi (cm2) | Volume (cm3) | GrossVolume (cm3) = NetVolume (cm3) | GrossFootprintArea (cm2) = NetFootprintArea (cm2) | GrossSideArea (cm2) = NetSideArea (cm2)
Enveloppe 205508 | 205508 | 0508 | 130.243 | 235 | 0 | 130.2 | 7700 | 30600 | 1810000 | 1792459 | 7627.49 | 30607.1
Enveloppe 153306 | 153306 | 0358 | 122.769 | 215 | -20 | 122.8 | 7200 | 26400 | 1560000 | 1545801 | 7189.77 | 26395.3

# IfcWallStandardCase: default 590, Enveloppe 128173
In: Niveau 1
Type - Material: <aucun> 59 cm
Description: Enveloppe; Group: ...de stratigraphies = default; ...de matériaux et couleurs = Ivoire clair; ...de matériaux et couleurs - 1 = Ivoire clair; ...de matériaux et couleurs - 2 = Ivoire clair
__RECOGNIZE__ - ID: 128173; TPLG: 366; TPLG_OD: 9000; GENERATE: 1
CTLG_EXTERNAL_LINK - 0, DocType: 2; 0, Tag: 0; 0, Crc: 1977773087; 1, DocType: 2; 1, Tag: 100; 1, Crc: 1977773087; 2, DocType: 2; 2, Tag: 200; 2, Crc: 1977773087; 3, DocType: 9; 3, Tag: 0; 3, Crc: 1184639922
IFC_PSET_PolygonOffset - polygonOffsetFactor: 2; polygonOffsetUnits: 2
IFC_Pset_Alignment - Alignment: 0
IFC_Pset_Strat_Detail_Align - ExternalFace: 0
IFC_Pset_Caractéristiques - ID: 128173; Numérotation: 0296; Numéro niveau: 04; Titre niveau: Niveau 1; Stratigraphie: default [590,00]; Épaisseur: 59 cm; Épaisseur VARIABLE: no
IFC_Pset_Caractéristiques_FRUIT - Fruit: no; Taille: 0 cm
IFC_Pset_Géométrie - Forme en Élévation: rectangle; Longueur: 64.4516 cm; Hauteur: 376.102 cm; Cote: 0.0128504 cm
IFC_Pset_Géométrie_P1 (POINT initial) - Hauteur: 376.102 cm; Cote: 0.0128504 cm; Angle XY: 359.988 deg
IFC_Pset_Géométrie_P2 (POINT final) - Hauteur: 376.102 cm; Cote: 0.0128504 cm; Angle XY: 179.988 deg
IFC_Pset_Système de Référence Altimétrique_SUPÉRIEUR - NIVEAU: HAUT Niveau 1 (Niveau 2 13545); delta: 0 cm; delta (P1): 0 cm; delta (P2): 0 cm; sous Niveau: <aucun>
IFC_Pset_Système de Référence Altimétrique_INFÉRIEUR - NIVEAU: Niveau 1 (Niveau 1 2343); delta: 0.0128504 cm; delta (P1): 0.0128504 cm; delta (P2): 0.0128504 cm; sous Niveau: <aucun>
IFC_Pset_Données Métré - Longueur Pied: 64.5 cm; Longueur Tête: 64.5 cm; Hauteur Maximale: 376.1 cm; Hauteur Minimale: 376.1 cm; Surface en Plan: 3800 cm2; Surface Pied: 3800 cm2; Surface Tête: 3800 cm2; Surface de la Paroi: 24300 cm2; Volume: 1430000 cm3
IFC_Pset_Matériaux - Face gauche: Ivoire clair; Face droite: Ivoire clair; Face latérale: Ivoire clair
Pset_WallCommon - Reference: default [590,00] (..\VERTICALES\Default\)
BaseQuantities - GrossVolume: 1430182 cm3; NetVolume: 1430182 cm3; NominalLength: 64.4516 cm; NominalWidth: 59 cm; NominalHeight: 376.102 cm; GrossFootprintArea: 3802.64 cm2; NetFootprintArea: 3802.64 cm2; GrossSideArea: 24240.4 cm2; NetSideArea: 24240.4 cm2

# IfcWallStandardCase: default 60 (44)
Type - Material: <aucun> 6 cm
Description: Enveloppe
__RECOGNIZE__ - TPLG: 366; TPLG_OD: 9000; GENERATE: 1
CTLG_EXTERNAL_LINK - 0, DocType: 2; 0, Tag: 0; 1, DocType: 2; 1, Tag: 100; 2, DocType: 2; 2, Tag: 200; 3, DocType: 9; 3, Tag: 0; 3, Crc: -662831384
IFC_PSET_PolygonOffset - polygonOffsetFactor: 2; polygonOffsetUnits: 2
IFC_Pset_Caractéristiques - Stratigraphie: default [60,00]; Épaisseur: 6 cm
IFC_Pset_Caractéristiques_FRUIT - Fruit: no; Taille: 0 cm
IFC_Pset_Système de Référence Altimétrique_SUPÉRIEUR - sous Niveau: <aucun>
IFC_Pset_Système de Référence Altimétrique_INFÉRIEUR - sous Niveau: <aucun>
Pset_WallCommon - Reference: default [60,00] (..\VERTICALES\Default\)
BaseQuantities - NominalWidth: 6 cm
Name | In | __RECOGNIZE__, ID = IFC_Pset_Caractéristiques, ID | 0, Crc = 1, Crc = 2, Crc | Alignment | ExternalFace | Numérotation | Numéro niveau | Titre niveau | Épaisseur VARIABLE | Forme en Élévation | Longueur (cm) = NominalLength (cm) | IFC_Pset_Géométrie, Hauteur (cm) = IFC_Pset_Géométrie_P1 (POINT initial), Hauteur (cm) | IFC_Pset_Géométrie, Cote (cm) = IFC_Pset_Géométrie_P1 (POINT initial), Cote (cm) = IFC_Pset_Géométrie_P2 (POINT final), Cote (cm) = IFC_Pset_Système de Référence Altimétrique_INFÉRIEUR, delta (cm) = IFC_Pset_Système de Référence Altimétrique_INFÉRIEUR, delta (P1) (cm) = IFC_Pset_Système de Référence Altimétrique_INFÉRIEUR, delta (P2) (cm) | IFC_Pset_Géométrie_P1 (POINT initial), Angle XY (deg) | IFC_Pset_Géométrie_P2 (POINT final), Hauteur (cm) | IFC_Pset_Géométrie_P2 (POINT final), Angle XY (deg) | IFC_Pset_Système de Référence Altimétrique_SUPÉRIEUR, NIVEAU | IFC_Pset_Système de Référence Altimétrique_SUPÉRIEUR, delta (cm) = IFC_Pset_Système de Référence Altimétrique_SUPÉRIEUR, delta (P1) (cm) = IFC_Pset_Système de Référence Altimétrique_SUPÉRIEUR, delta (P2) (cm) | IFC_Pset_Système de Référence Altimétrique_INFÉRIEUR, NIVEAU | Longueur Pied (cm) | Longueur Tête (cm) | Hauteur Maximale (cm) | Hauteur Minimale (cm) | Surface en Plan (cm2) = Surface Pied (cm2) | Surface Tête (cm2) | Surface de la Paroi (cm2) | Volume (cm3) | Face gauche = Face droite = Face latérale | GrossVolume (cm3) | NetVolume (cm3) | NominalHeight (cm) | GrossFootprintArea (cm2) = NetFootprintArea (cm2) | GrossSideArea (cm2) | NetSideArea (cm2) | Group
Enveloppe 72513 | Rez-de-Jardin | 72513 | 1977773087 | 0 | 1 | 0162 | 02 | Rez-de-Jardin | no | rectangle | 370.007 | 291.413 | -1.94511e-11 | 89.5447 | 291.413 | 269.545 | HAUT Rez-de-Jardin (Rez-de-chaussée 1047) | 0.0128504 | Rez-de-Jardin (Rez-de-Jardin 15545) | 370 | 370 | 291.4 | 291.4 | 2200 | 2200 | 107800 | 650000 | Ivoire clair | 646949 | 180784 | 291.413 | 2220.04 | 107825 | 30130.7 | ...de stratigraphies = default; ...de matériaux et couleurs = Ivoire clair; ...de matériaux et couleurs - 1 = Ivoire clair; ...de matériaux et couleurs - 2 = Ivoire clair
Enveloppe 73902 | Rez-de-Jardin | 73902 | 1977773087 | 1 | 1 | 0165 | 02 | Rez-de-Jardin | no | rectangle | 158.502 | 291.413 | -1.94511e-11 | 0.304158 | 291.413 | 180.304 | HAUT Rez-de-Jardin (Rez-de-chaussée 1047) | 0.0128504 | Rez-de-Jardin (Rez-de-Jardin 15545) | 158.5 | 158.5 | 291.4 | 291.4 | 1000 | 1000 | 46200 | 280000 | Ivoire clair | 277137 | 84693.3 | 291.413 | 951.012 | 46189.6 | 14115.6 | ...de stratigraphies = default; ...de matériaux et couleurs = Ivoire clair; ...de matériaux et couleurs - 1 = Ivoire clair; ...de matériaux et couleurs - 2 = Ivoire clair
Enveloppe 73929 | Rez-de-Jardin | 73929 | 347490523 | 0 | 1 | 0166 | 02 | Rez-de-Jardin | no | rectangle | 29.2205 | 291.413 | -1.94511e-11 | 0.286032 | 291.413 | 180.286 | HAUT Rez-de-Jardin (Rez-de-chaussée 1047) | 0.0128504 | Rez-de-Jardin (Rez-de-Jardin 15545) | 29.2 | 29.2 | 291.4 | 291.4 | 200 | 200 | 8500 | 50000 | Noir graphite | 51091.5 | 51091.5 | 291.413 | 175.323 | 8515.25 | 8515.25 | ...de stratigraphies = default; ...de matériaux et couleurs = Noir graphite; ...de matériaux et couleurs - 1 = Noir graphite; ...de matériaux et couleurs - 2 = Noir graphite
Enveloppe 73989 | Rez-de-Jardin | 73989 | 347490523 | 0 | 1 | 0169 | 02 | Rez-de-Jardin | no | rectangle | 29.0436 | 291.413 | -1.94511e-11 | 89.6809 | 291.413 | 269.681 | HAUT Rez-de-Jardin (Rez-de-chaussée 1047) | 0.0128504 | Rez-de-Jardin (Rez-de-Jardin 15545) | 29 | 29 | 291.4 | 291.4 | 200 | 200 | 8500 | 50000 | Noir graphite | 50782.1 | 50782.1 | 291.413 | 174.261 | 8463.68 | 8463.68 | ...de stratigraphies = default; ...de matériaux et couleurs = Noir graphite; ...de matériaux et couleurs - 1 = Noir graphite; ...de matériaux et couleurs - 2 = Noir graphite
Enveloppe 73951 | Rez-de-Jardin | 73951 | 347490523 | 1 | 1 | 0167 | 02 | Rez-de-Jardin | no | rectangle | 29.7537 | 291.413 | -1.94511e-11 | 89.8612 | 291.413 | 269.861 | HAUT Rez-de-Jardin (Rez-de-chaussée 1047) | 0.0128504 | Rez-de-Jardin (Rez-de-Jardin 15545) | 29.8 | 29.8 | 291.4 | 291.4 | 200 | 200 | 8700 | 50000 | Noir graphite | 52023.7 | 52023.7 | 291.413 | 178.522 | 8670.62 | 8670.62 | ...de stratigraphies = default; ...de matériaux et couleurs = Noir graphite; ...de matériaux et couleurs - 1 = Noir graphite; ...de matériaux et couleurs - 2 = Noir graphite
Enveloppe 73967 | Rez-de-Jardin | 73967 | 347490523 | 0 | 1 | 0168 | 02 | Rez-de-Jardin | no | rectangle | 29.4873 | 291.413 | -1.94511e-11 | 179.523 | 291.413 | 359.523 | HAUT Rez-de-Jardin (Rez-de-chaussée 1047) | 0.0128504 | Rez-de-Jardin (Rez-de-Jardin 15545) | 29.5 | 29.5 | 291.4 | 291.4 | 200 | 200 | 8600 | 50000 | Noir graphite | 51557.9 | 51557.9 | 291.413 | 176.924 | 8592.99 | 8592.99 | ...de stratigraphies = default; ...de matériaux et couleurs = Noir graphite; ...de matériaux et couleurs - 1 = Noir graphite; ...de matériaux et couleurs - 2 = Noir graphite
Enveloppe 92784 | Niveau 1 | 92784 | 1977773087 | 1 | 0 | 0193 | 04 | Niveau 1 | yes | rectangle | 100.602 | 376.102 | 0.0128504 | 179.905 | 376.102 | 359.905 | HAUT Niveau 1 (Niveau 2 13545) | 0 | Niveau 1 (Niveau 1 2343) | 100.6 | 100.6 | 376.1 | 376.1 | 600 | 600 | 37800 | 230000 | Ivoire clair | 227020 | 109286 | 376.102 | 603.614 | 37836.7 | 18214.3 | ...de stratigraphies = default; ...de matériaux et couleurs = Ivoire clair; ...de matériaux et couleurs - 1 = Ivoire clair; ...de matériaux et couleurs - 2 = Ivoire clair
Enveloppe 93384 | Niveau 1 | 93384 | 1977773087 | 0 | 0 | 0204 | 04 | Niveau 1 | no | rectangle | 75.2123 | 376.102 | 0.0128504 | 89.8395 | 376.102 | 269.839 | HAUT Niveau 1 (Niveau 2 13545) | 0 | Niveau 1 (Niveau 1 2343) | 75.2 | 75.2 | 376.1 | 376.1 | 500 | 500 | 28300 | 170000 | Ivoire clair | 169725 | 169725 | 376.102 | 451.274 | 28287.5 | 28287.5 | ...de stratigraphies = default; ...de matériaux et couleurs = Ivoire clair; ...de matériaux et couleurs - 1 = Ivoire clair; ...de matériaux et couleurs - 2 = Ivoire clair
Enveloppe 93395 | Niveau 1 | 93395 | 1977773087 | 0 | 0 | 0205 | 04 | Niveau 1 | no | rectangle | 149.228 | 376.102 | 0.0128504 | 0.120163 | 376.102 | 180.12 | HAUT Niveau 1 (Niveau 2 13545) | 0 | Niveau 1 (Niveau 1 2343) | 149.2 | 149.2 | 376.1 | 376.1 | 900 | 900 | 56100 | 340000 | Ivoire clair | 336749 | 336749 | 376.102 | 895.365 | 56124.8 | 56124.8 | ...de stratigraphies = default; ...de matériaux et couleurs = Ivoire clair; ...de matériaux et couleurs - 1 = Ivoire clair; ...de matériaux et couleurs - 2 = Ivoire clair
Enveloppe 92438 | Niveau 1 | 92438 | 1977773087 | 0 | 0 | 0183 | 04 | Niveau 1 | no | rectangle | 145.786 | 376.102 | 0.0128504 | 0.689891 | 376.102 | 180.69 | HAUT Niveau 1 (Niveau 2 13545) | 0 | Niveau 1 (Niveau 1 2343) | 145.8 | 145.8 | 376.1 | 376.1 | 900 | 900 | 54800 | 330000 | Ivoire clair | 328982 | 328982 | 376.102 | 874.715 | 54830.3 | 54830.3 | ...de stratigraphies = default; ...de matériaux et couleurs = Ivoire clair; ...de matériaux et couleurs - 1 = Ivoire clair; ...de matériaux et couleurs - 2 = Ivoire clair
Enveloppe 92513 | Niveau 1 | 92513 | 1977773087 | 1 | 0 | 0184 | 04 | Niveau 1 | yes | rectangle | 358.508 | 376.102 | 0.0128504 | 89.7486 | 376.102 | 269.749 | HAUT Niveau 1 (Niveau 2 13545) | 0 | Niveau 1 (Niveau 1 2343) | 358.5 | 358.5 | 376.1 | 376.1 | 2200 | 2200 | 134800 | 810000 | Ivoire clair | 809013 | 718296 | 376.102 | 2151.05 | 134835 | 119716 | ...de stratigraphies = default; ...de matériaux et couleurs = Ivoire clair; ...de matériaux et couleurs - 1 = Ivoire clair; ...de matériaux et couleurs - 2 = Ivoire clair
Enveloppe 104149 | Niveau 1 | 104149 | 1977773087 | 1 | 0 | 0262 | 04 | Niveau 1 | no | rectangle | 64.006 | 298.702 | 0.0128504 | 90.0076 | 298.702 | 270.008 | HAUT Niveau 1 (Niveau 2 13545) | -77.4 | Niveau 1 (Niveau 1 2343) | 64 | 64 | 298.7 | 298.7 | 400 | 400 | 19100 | 110000 | Ivoire clair | 114712 | 114712 | 298.702 | 384.036 | 19118.7 | 19118.7 | ...de stratigraphies = default; ...de matériaux et couleurs = Ivoire clair; ...de matériaux et couleurs - 1 = Ivoire clair; ...de matériaux et couleurs - 2 = Ivoire clair
Enveloppe 104800 | Niveau 1 | 104800 | 1977773087 | 0 | 0 | 0267 | 04 | Niveau 1 | no | rectangle | 63.874 | 298.702 | 0.0128504 | 88.9443 | 298.702 | 268.944 | HAUT Niveau 1 (Niveau 2 13545) | -77.4 | Niveau 1 (Niveau 1 2343) | 63.9 | 63.9 | 298.7 | 298.7 | 400 | 400 | 19100 | 110000 | Ivoire clair | 114476 | 114476 | 298.702 | 383.244 | 19079.3 | 19079.3 | ...de stratigraphies = default; ...de matériaux et couleurs = Ivoire clair; ...de matériaux et couleurs - 1 = Ivoire clair; ...de matériaux et couleurs - 2 = Ivoire clair
Enveloppe 104771 | Niveau 1 | 104771 | 1977773087 | 1 | 0 | 0266 | 04 | Niveau 1 | no | rectangle | 63.9499 | 298.702 | 0.0128504 | 90.9329 | 298.702 | 270.933 | HAUT Niveau 1 (Niveau 2 13545) | -77.4 | Niveau 1 (Niveau 1 2343) | 63.9 | 63.9 | 298.7 | 298.7 | 400 | 400 | 19100 | 110000 | Ivoire clair | 114612 | 114612 | 298.702 | 383.699 | 19102 | 19102 | ...de stratigraphies = default; ...de matériaux et couleurs = Ivoire clair; ...de matériaux et couleurs - 1 = Ivoire clair; ...de matériaux et couleurs - 2 = Ivoire clair
Enveloppe 116205 | Niveau 1 | 116205 | 1977773087 | 0 | 0 | 0281 | 04 | Niveau 1 | no | rectangle | 97.8605 | 230.987 | 0.0128504 | 0.213024 | 230.987 | 180.213 | HAUT Niveau 1 (Niveau 2 13545) | -145.115 | Niveau 1 (Niveau 1 2343) | 97.9 | 97.9 | 231 | 231 | 600 | 600 | 22600 | 140000 | Ivoire clair | 135627 | 17637.1 | 230.987 | 587.163 | 22604.5 | 2939.51 | ...de stratigraphies = default; ...de matériaux et couleurs = Ivoire clair; ...de matériaux et couleurs - 1 = Ivoire clair; ...de matériaux et couleurs - 2 = Ivoire clair
Enveloppe 103209 | Niveau 1 | 103209 | 1977773087 | 1 | 0 | 0253 | 04 | Niveau 1 | no | rectangle | 122.611 | 376.102 | 0.0128504 | 90.3835 | 376.102 | 270.384 | HAUT Niveau 1 (Niveau 2 13545) | 0 | Niveau 1 (Niveau 1 2343) | 122.6 | 122.6 | 376.1 | 376.1 | 700 | 700 | 46100 | 280000 | Ivoire clair | 276684 | 193310 | 376.102 | 735.663 | 46114.1 | 32218.3 | ...de stratigraphies = default; ...de matériaux et couleurs = Ivoire clair; ...de matériaux et couleurs - 1 = Ivoire clair; ...de matériaux et couleurs - 2 = Ivoire clair
Enveloppe 103947 | Niveau 1 | 103947 | 1977773087 | 0 | 0 | 0257 | 04 | Niveau 1 | no | rectangle | 58.0163 | 298.702 | 0.0128504 | 91.1584 | 298.702 | 271.158 | HAUT Niveau 1 (Niveau 2 13545) | -77.4 | Niveau 1 (Niveau 1 2343) | 58 | 58 | 298.7 | 298.7 | 300 | 300 | 17300 | 100000 | Ivoire clair | 103977 | 103977 | 298.702 | 348.098 | 17329.6 | 17329.6 | ...de stratigraphies = default; ...de matériaux et couleurs = Ivoire clair; ...de matériaux et couleurs - 1 = Ivoire clair; ...de matériaux et couleurs - 2 = Ivoire clair
Enveloppe 103995 | Niveau 1 | 103995 | 1977773087 | 1 | 0 | 0258 | 04 | Niveau 1 | no | rectangle | 98.3165 | 376.102 | 0.0128504 | 179.932 | 376.102 | 359.932 | HAUT Niveau 1 (Niveau 2 13545) | 0 | Niveau 1 (Niveau 1 2343) | 98.3 | 98.3 | 376.1 | 376.1 | 600 | 600 | 37000 | 220000 | Ivoire clair | 221862 | 221862 | 376.102 | 589.899 | 36977 | 36977 | ...de stratigraphies = default; ...de matériaux et couleurs = Ivoire clair; ...de matériaux et couleurs - 1 = Ivoire clair; ...de matériaux et couleurs - 2 = Ivoire clair
Enveloppe 103698 | Niveau 1 | 103698 | 1977773087 | 0 | 0 | 0255 | 04 | Niveau 1 | no | rectangle | 69.2588 | 298.702 | 0.0128504 | 90.8358 | 298.702 | 270.836 | HAUT Niveau 1 (Niveau 2 13545) | -77.4 | Niveau 1 (Niveau 1 2343) | 69.3 | 69.3 | 298.7 | 298.7 | 400 | 400 | 20700 | 120000 | Ivoire clair | 124127 | 124127 | 298.702 | 415.553 | 20687.8 | 20687.8 | ...de stratigraphies = default; ...de matériaux et couleurs = Ivoire clair; ...de matériaux et couleurs - 1 = Ivoire clair; ...de matériaux et couleurs - 2 = Ivoire clair
Enveloppe 103902 | Niveau 1 | 103902 | 1977773087 | 0 | 0 | 0256 | 04 | Niveau 1 | no | rectangle | 48.2728 | 376.102 | 0.0128504 | 1.06649 | 376.102 | 181.066 | HAUT Niveau 1 (Niveau 2 13545) | 0 | Niveau 1 (Niveau 1 2343) | 48.3 | 48.3 | 376.1 | 376.1 | 300 | 300 | 18200 | 110000 | Ivoire clair | 108933 | 108933 | 376.102 | 289.637 | 18155.5 | 18155.5 | ...de stratigraphies = default; ...de matériaux et couleurs = Ivoire clair; ...de matériaux et couleurs - 1 = Ivoire clair; ...de matériaux et couleurs - 2 = Ivoire clair
Enveloppe 104140 | Niveau 1 | 104140 | 1977773087 | 1 | 0 | 0261 | 04 | Niveau 1 | no | rectangle | 292.764 | 298.702 | 0.0128504 | 0.22243 | 298.702 | 180.222 | HAUT Niveau 1 (Niveau 2 13545) | -77.4 | Niveau 1 (Niveau 1 2343) | 292.8 | 292.8 | 298.7 | 298.7 | 1800 | 1800 | 87500 | 530000 | Ivoire clair | 524696 | 212106 | 298.702 | 1756.59 | 87449.3 | 35350.9 | ...de stratigraphies = default; ...de matériaux et couleurs = Ivoire clair; ...de matériaux et couleurs - 1 = Ivoire clair; ...de matériaux et couleurs - 2 = Ivoire clair
Enveloppe 104133 | Niveau 1 | 104133 | 1977773087 | 0 | 0 | 0260 | 04 | Niveau 1 | no | rectangle | 393.899 | 376.102 | 0.0128504 | 0.22243 | 376.102 | 180.222 | HAUT Niveau 1 (Niveau 2 13545) | 0 | Niveau 1 (Niveau 1 2343) | 393.9 | 393.9 | 376.1 | 376.1 | 2400 | 2400 | 148100 | 890000 | Ivoire clair | 888877 | 782459 | 376.102 | 2363.39 | 148146 | 130410 | ...de stratigraphies = default; ...de matériaux et couleurs = Ivoire clair; ...de matériaux et couleurs - 1 = Ivoire clair; ...de matériaux et couleurs - 2 = Ivoire clair
Enveloppe 92552 | Niveau 1 | 92552 | 1977773087 | 1 | 0 | 0185 | 04 | Niveau 1 | no | rectangle | 291.656 | 298.702 | 0.0128504 | 0.22243 | 298.702 | 180.222 | HAUT Niveau 1 (Niveau 2 13545) | -77.4 | Niveau 1 (Niveau 1 2343) | 291.6 | 291.6 | 298.7 | 298.7 | 1800 | 1800 | 87100 | 520000 | Ivoire clair | 522709 | 213014 | 298.702 | 1749.94 | 87118.2 | 35502.4 | ...de stratigraphies = default; ...de matériaux et couleurs = Ivoire clair; ...de matériaux et couleurs - 1 = Ivoire clair; ...de matériaux et couleurs - 2 = Ivoire clair
Enveloppe 176780 | Niveau 2 | 176780 | 1977773087 | 0 | 0 | 0456 | 05 | Niveau 2 | no | rectangle | 32.2673 | 235 | 1.42109e-12 | 91.2124 | 235 | 271.212 | HAUT Niveau 2 (Mezzanine 49003) | 1.42109e-12 | Niveau 2 (Niveau 2 13545) | 32.3 | 32.3 | 235 | 235 | 200 | 200 | 7600 | 50000 | Ivoire clair | 45496.9 | 45496.9 | 235 | 193.604 | 7582.81 | 7582.81 | ...de stratigraphies = default; ...de matériaux et couleurs = Ivoire clair; ...de matériaux et couleurs - 1 = Ivoire clair; ...de matériaux et couleurs - 2 = Ivoire clair
Enveloppe 176690 | Niveau 2 | 176690 | 1977773087 | 0 | 0 | 0454 | 05 | Niveau 2 | no | rectangle | 317.835 | 235 | 1.42109e-12 | 0.247136 | 235 | 180.247 | HAUT Niveau 2 (Mezzanine 49003) | 1.42109e-12 | Niveau 2 (Niveau 2 13545) | 317.8 | 317.8 | 235 | 235 | 1900 | 1900 | 74700 | 450000 | Ivoire clair | 448147 | 448147 | 235 | 1907.01 | 74691.1 | 74691.1 | ...de stratigraphies = default; ...de matériaux et couleurs = Ivoire clair; ...de matériaux et couleurs - 1 = Ivoire clair; ...de matériaux et couleurs - 2 = Ivoire clair
Enveloppe 176740 | Niveau 2 | 176740 | 1977773087 | 1 | 0 | 0455 | 05 | Niveau 2 | no | rectangle | 20 | 225 | 1.42109e-12 | 92.702 | 225 | 272.702 | HAUT Niveau 2 (Mezzanine 49003) | -10 | Niveau 2 (Niveau 2 13545) | 20 | 20 | 225 | 225 | 100 | 100 | 4500 | 30000 | Ivoire clair | 27000 | 27000 | 225 | 120 | 4500 | 4500 | ...de stratigraphies = default; ...de matériaux et couleurs = Ivoire clair; ...de matériaux et couleurs - 1 = Ivoire clair; ...de matériaux et couleurs - 2 = Ivoire clair
Enveloppe 176069 | Niveau 2 | 176069 | 1977773087 | 1 | 0 | 0447 | 05 | Niveau 2 | no | rectangle | 87.9552 | 222 | 1.42109e-12 | 89.6354 | 222 | 269.635 | HAUT Niveau 2 (Mezzanine 49003) | -13 | Niveau 2 (Niveau 2 13545) | 88 | 88 | 222 | 222 | 500 | 500 | 19500 | 120000 | Ivoire clair | 117156 | 33774.8 | 222 | 527.731 | 19526.1 | 5629.13 | ...de stratigraphies = default; ...de matériaux et couleurs = Ivoire clair; ...de matériaux et couleurs - 1 = Ivoire clair; ...de matériaux et couleurs - 2 = Ivoire clair
Enveloppe 176222 | Niveau 2 | 176222 | 1977773087 | 1 | 0 | 0448 | 05 | Niveau 2 | no | rectangle | 36.4306 | 222 | 1.42109e-12 | 90.7572 | 222 | 270.757 | HAUT Niveau 2 (Mezzanine 49003) | -13 | Niveau 2 (Niveau 2 13545) | 36.4 | 36.4 | 222 | 222 | 200 | 200 | 8100 | 50000 | Ivoire clair | 48525.5 | 48525.5 | 222 | 218.583 | 8087.58 | 8087.58 | ...de stratigraphies = default; ...de matériaux et couleurs = Ivoire clair; ...de matériaux et couleurs - 1 = Ivoire clair; ...de matériaux et couleurs - 2 = Ivoire clair
Enveloppe 175841 | Niveau 2 | 175841 | 1977773087 | 0 | 0 | 0445 | 05 | Niveau 2 | no | rectangle | 37.4511 | 225 | 1.42109e-12 | 169.144 | 225 | 349.144 | HAUT Niveau 2 (Mezzanine 49003) | -10 | Niveau 2 (Niveau 2 13545) | 37.5 | 37.5 | 225 | 225 | 200 | 200 | 8400 | 50000 | Ivoire clair | 50558.9 | 50558.9 | 225 | 224.706 | 8426.49 | 8426.49 | ...de stratigraphies = default; ...de matériaux et couleurs = Ivoire clair; ...de matériaux et couleurs - 1 = Ivoire clair; ...de matériaux et couleurs - 2 = Ivoire clair
Enveloppe 175987 | Niveau 2 | 175987 | 1977773087 | 1 | 0 | 0446 | 05 | Niveau 2 | no | rectangle | 42.5263 | 222 | 1.42109e-12 | 179.189 | 222 | 359.189 | HAUT Niveau 2 (Mezzanine 49003) | -13 | Niveau 2 (Niveau 2 13545) | 42.5 | 42.5 | 222 | 222 | 300 | 300 | 9400 | 60000 | Ivoire clair | 56645 | 56645 | 222 | 255.158 | 9440.83 | 9440.83 | ...de stratigraphies = default; ...de matériaux et couleurs = Ivoire clair; ...de matériaux et couleurs - 1 = Ivoire clair; ...de matériaux et couleurs - 2 = Ivoire clair
Enveloppe 176242 | Niveau 2 | 176242 | 1977773087 | 1 | 0 | 0449 | 05 | Niveau 2 | no | rectangle | 38.1631 | 222 | 1.42109e-12 | 6.04649 | 222 | 186.046 | HAUT Niveau 2 (Mezzanine 49003) | -13 | Niveau 2 (Niveau 2 13545) | 38.2 | 38.2 | 222 | 222 | 200 | 200 | 8500 | 50000 | Ivoire clair | 50833.3 | 50833.3 | 222 | 228.979 | 8472.22 | 8472.22 | ...de stratigraphies = default; ...de matériaux et couleurs = Ivoire clair; ...de matériaux et couleurs - 1 = Ivoire clair; ...de matériaux et couleurs - 2 = Ivoire clair
Enveloppe 176519 | Niveau 2 | 176519 | 1977773087 | 1 | 0 | 0452 | 05 | Niveau 2 | no | rectangle | 103.855 | 222 | 1.42109e-12 | 91.1201 | 222 | 271.12 | HAUT Niveau 2 (Mezzanine 49003) | -13 | Niveau 2 (Niveau 2 13545) | 103.9 | 103.9 | 222 | 222 | 600 | 600 | 23100 | 140000 | Ivoire clair | 138335 | 138335 | 222 | 623.129 | 23055.8 | 23055.8 | ...de stratigraphies = default; ...de matériaux et couleurs = Ivoire clair; ...de matériaux et couleurs - 1 = Ivoire clair; ...de matériaux et couleurs - 2 = Ivoire clair
Enveloppe 176538 | Niveau 2 | 176538 | 1977773087 | 0 | 0 | 0453 | 05 | Niveau 2 | no | rectangle | 87.5585 | 235 | 1.42109e-12 | 1.31471 | 235 | 181.315 | HAUT Niveau 2 (Mezzanine 49003) | 1.42109e-12 | Niveau 2 (Niveau 2 13545) | 87.6 | 87.6 | 235 | 235 | 500 | 500 | 20600 | 120000 | Ivoire clair | 123457 | 123457 | 235 | 525.351 | 20576.2 | 20576.2 | ...de stratigraphies = default; ...de matériaux et couleurs = Ivoire clair; ...de matériaux et couleurs - 1 = Ivoire clair; ...de matériaux et couleurs - 2 = Ivoire clair
Enveloppe 176262 | Niveau 2 | 176262 | 1977773087 | 1 | 0 | 0450 | 05 | Niveau 2 | no | rectangle | 90.8194 | 222 | 1.42109e-12 | 89.5907 | 222 | 269.591 | HAUT Niveau 2 (Mezzanine 49003) | -13 | Niveau 2 (Niveau 2 13545) | 90.8 | 90.8 | 222 | 222 | 500 | 500 | 20200 | 120000 | Ivoire clair | 120971 | 36060.1 | 222 | 544.916 | 20161.9 | 6010.01 | ...de stratigraphies = default; ...de matériaux et couleurs = Ivoire clair; ...de matériaux et couleurs - 1 = Ivoire clair; ...de matériaux et couleurs - 2 = Ivoire clair
Enveloppe 176439 | Niveau 2 | 176439 | 1977773087 | 1 | 0 | 0451 | 05 | Niveau 2 | no | rectangle | 39.2615 | 222 | 1.42109e-12 | 177.612 | 222 | 357.612 | HAUT Niveau 2 (Mezzanine 49003) | -13 | Niveau 2 (Niveau 2 13545) | 39.3 | 39.3 | 222 | 222 | 200 | 200 | 8700 | 50000 | Ivoire clair | 52296.3 | 52296.3 | 222 | 235.569 | 8716.05 | 8716.05 | ...de stratigraphies = default; ...de matériaux et couleurs = Ivoire clair; ...de matériaux et couleurs - 1 = Ivoire clair; ...de matériaux et couleurs - 2 = Ivoire clair
Enveloppe 175681 | Niveau 2 | 175681 | 1977773087 | 0 | 0 | 0444 | 05 | Niveau 2 | no | rectangle | 56.0448 | 225 | 1.42109e-12 | 1.01822 | 225 | 181.018 | HAUT Niveau 2 (Mezzanine 49003) | -10 | Niveau 2 (Niveau 2 13545) | 56 | 56 | 225 | 225 | 300 | 300 | 12600 | 80000 | Ivoire clair | 75660.5 | 75660.5 | 225 | 336.269 | 12610.1 | 12610.1 | ...de stratigraphies = default; ...de matériaux et couleurs = Ivoire clair; ...de matériaux et couleurs - 1 = Ivoire clair; ...de matériaux et couleurs - 2 = Ivoire clair
Enveloppe 158717 | Niveau 2 | 158717 | 1977773087 | 0 | 0 | 0362 | 05 | Niveau 2 | no | rectangle | 97.8074 | 210 | 1.42109e-12 | 89.9993 | 210 | 269.999 | HAUT Niveau 2 (Mezzanine 49003) | -25 | Niveau 2 (Niveau 2 13545) | 97.8 | 97.8 | 210 | 210 | 600 | 600 | 20500 | 120000 | Ivoire clair | 123237 | 1603.72 | 210 | 586.845 | 20539.6 | 267.287 | ...de stratigraphies = default; ...de matériaux et couleurs = Ivoire clair; ...de matériaux et couleurs - 1 = Ivoire clair; ...de matériaux et couleurs - 2 = Ivoire clair
Enveloppe 168356 | Niveau 2 | 168356 | 1977773087 | 1 | 0 | 0417 | 05 | Niveau 2 | no | rectangle | 130.052 | 222 | 1.42109e-12 | 0.0874921 | 222 | 180.087 | HAUT Niveau 2 (Mezzanine 49003) | -13 | Niveau 2 (Niveau 2 13545) | 130.1 | 130.1 | 222 | 222 | 800 | 800 | 28900 | 170000 | Ivoire clair | 173230 | 173230 | 222 | 780.315 | 28871.6 | 28871.6 | ...de stratigraphies = default; ...de matériaux et couleurs = Ivoire clair; ...de matériaux et couleurs - 1 = Ivoire clair; ...de matériaux et couleurs - 2 = Ivoire clair
Enveloppe 170343 | Niveau 2 | 170343 | 1977773087 | 0 | 0 | 0421 | 05 | Niveau 2 | no | trapèze | 104.524 | 402.105 | 1.42109e-12 | 90.8566 | 294.702 | 270.857 | HAUT Mezzanine (Couverture 2134) | 0 | Niveau 2 (Niveau 2 13545) | 104.5 | 149.8 | 402.1 | 294.7 | 600 | 900 | 36400 | 220000 | Ivoire clair | 218500 | 99504.6 | 348.404 | 627.146 | 36416.6 | 16584.1 | ...de stratigraphies = default; ...de matériaux et couleurs = Ivoire clair; ...de matériaux et couleurs - 1 = Ivoire clair; ...de matériaux et couleurs - 2 = Ivoire clair
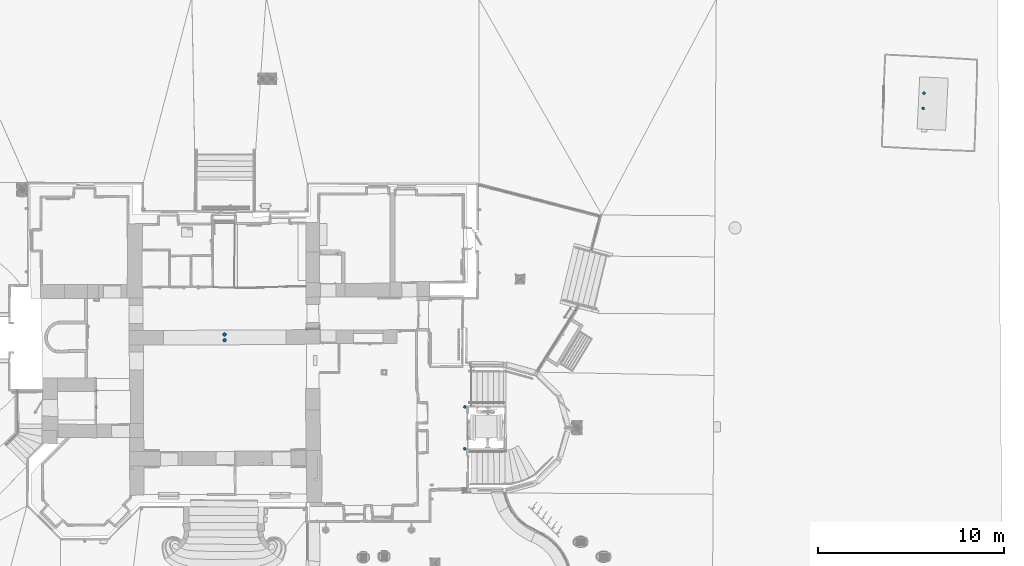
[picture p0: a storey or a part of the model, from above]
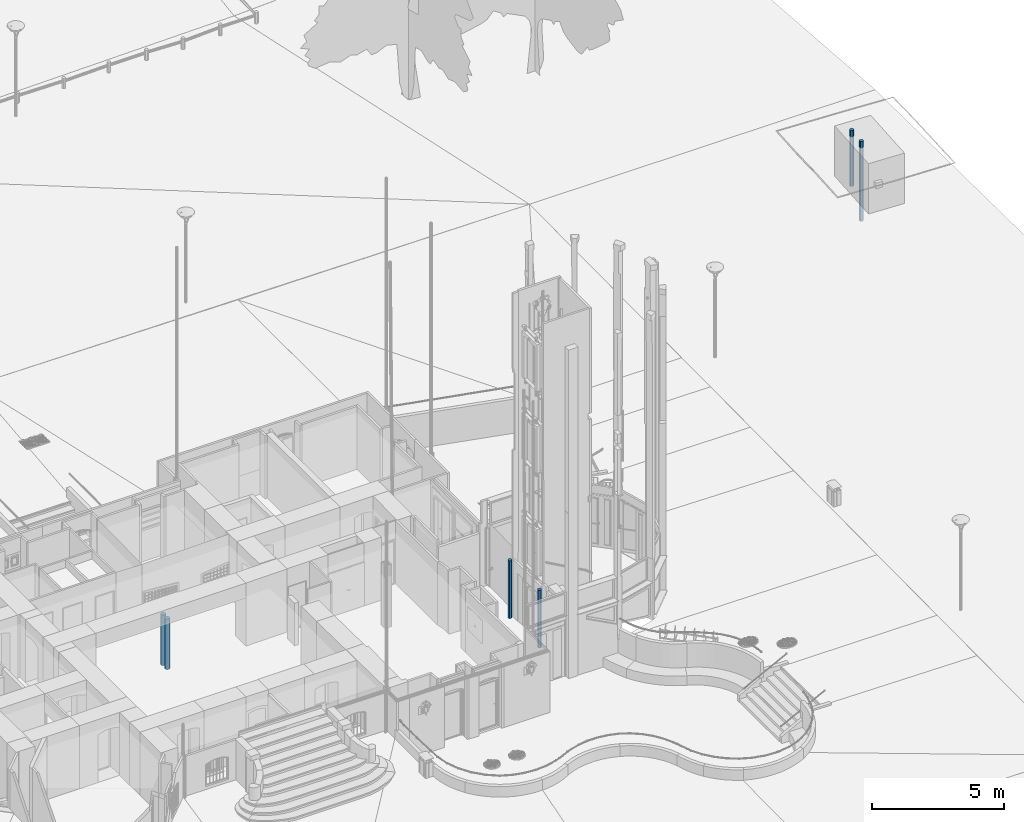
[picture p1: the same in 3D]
Properties of the parts of a building model (IFC2X3), part 26 of 37

# IfcWallStandardCase: default 60 (44)
Name | In | __RECOGNIZE__, ID = IFC_Pset_Caractéristiques, ID | 0, Crc = 1, Crc = 2, Crc | Alignment | ExternalFace | Numérotation | Numéro niveau | Titre niveau | Épaisseur VARIABLE | Forme en Élévation | Longueur (cm) = NominalLength (cm) | IFC_Pset_Géométrie, Hauteur (cm) = IFC_Pset_Géométrie_P1 (POINT initial), Hauteur (cm) | IFC_Pset_Géométrie, Cote (cm) = IFC_Pset_Géométrie_P1 (POINT initial), Cote (cm) = IFC_Pset_Géométrie_P2 (POINT final), Cote (cm) = IFC_Pset_Système de Référence Altimétrique_INFÉRIEUR, delta (cm) = IFC_Pset_Système de Référence Altimétrique_INFÉRIEUR, delta (P1) (cm) = IFC_Pset_Système de Référence Altimétrique_INFÉRIEUR, delta (P2) (cm) | IFC_Pset_Géométrie_P1 (POINT initial), Angle XY (deg) | IFC_Pset_Géométrie_P2 (POINT final), Hauteur (cm) | IFC_Pset_Géométrie_P2 (POINT final), Angle XY (deg) | IFC_Pset_Système de Référence Altimétrique_SUPÉRIEUR, NIVEAU | IFC_Pset_Système de Référence Altimétrique_SUPÉRIEUR, delta (cm) = IFC_Pset_Système de Référence Altimétrique_SUPÉRIEUR, delta (P1) (cm) = IFC_Pset_Système de Référence Altimétrique_SUPÉRIEUR, delta (P2) (cm) | IFC_Pset_Système de Référence Altimétrique_INFÉRIEUR, NIVEAU | Longueur Pied (cm) | Longueur Tête (cm) | Hauteur Maximale (cm) | Hauteur Minimale (cm) | Surface en Plan (cm2) = Surface Pied (cm2) | Surface Tête (cm2) | Surface de la Paroi (cm2) | Volume (cm3) | Face gauche = Face droite = Face latérale | GrossVolume (cm3) | NetVolume (cm3) | NominalHeight (cm) | GrossFootprintArea (cm2) = NetFootprintArea (cm2) | GrossSideArea (cm2) | NetSideArea (cm2) | Group
Enveloppe 225974 | Mezzanine | 225974 | -1156274542 | 0 | 1 | 0512 | 06 | Mezzanine | yes | rectangle | 96.0419 | 132.005 | 48 | 0.148037 | 132.005 | 180.148 | HAUT Mezzanine (Couverture 2134) | -99.6977 | Mezzanine (Mezzanine 49003) | 96 | 96 | 132 | 132 | 600 | 600 | 12700 | 80000 | Chêne | 76068 | 76068 | 132.005 | 576.252 | 12678 | 12678 | ...de matériaux et couleurs = Chêne; ...de stratigraphies = default; ...de matériaux et couleurs - 1 = Chêne; ...de matériaux et couleurs - 2 = Chêne
Enveloppe 192890 | Mezzanine | 192890 | -1156274542 | 1 | 1 | 0476 | 06 | Mezzanine | yes | rectangle | 130.927 | 130.005 | 50 | 0.128764 | 130.005 | 180.129 | HAUT Mezzanine (Couverture 2134) | -99.6977 | Mezzanine (Mezzanine 49003) | 130.9 | 130.9 | 130 | 130 | 800 | 800 | 17000 | 100000 | Chêne | 102127 | 102127 | 130.005 | 785.563 | 17021.1 | 17021.1 | ...de matériaux et couleurs = Chêne; ...de stratigraphies = default; ...de matériaux et couleurs - 1 = Chêne; ...de matériaux et couleurs - 2 = Chêne
Enveloppe 193857 | Mezzanine | 193857 | -1156274542 | 0 | 1 | 0479 | 06 | Mezzanine | yes | rectangle | 170.974 | 133.005 | 47 | 0.148037 | 133.005 | 180.148 | HAUT Mezzanine (Couverture 2134) | -99.6977 | Mezzanine (Mezzanine 49003) | 171 | 171 | 133 | 133 | 1000 | 1000 | 22700 | 140000 | Chêne | 136442 | 136442 | 133.005 | 1025.84 | 22740.3 | 22740.3 | ...de matériaux et couleurs = Chêne; ...de stratigraphies = default; ...de matériaux et couleurs - 1 = Chêne; ...de matériaux et couleurs - 2 = Chêne
Enveloppe 193067 | Mezzanine | 193067 | -1156274542 | 0 | 0 | 0477 | 06 | Mezzanine | yes | rectangle | 315.046 | 130.005 | 50 | 90.0569 | 130.005 | 270.057 | HAUT Mezzanine (Couverture 2134) | -99.6977 | Mezzanine (Mezzanine 49003) | 315 | 315 | 130 | 130 | 1900 | 1900 | 41000 | 250000 | Chêne | 245745 | 245745 | 130.005 | 1890.28 | 40957.5 | 40957.5 | ...de matériaux et couleurs = Chêne; ...de stratigraphies = default; ...de matériaux et couleurs - 1 = Chêne; ...de matériaux et couleurs - 2 = Chêne
Enveloppe 193082 | Mezzanine | 193082 | -1156274542 | 0 | 1 | 0478 | 06 | Mezzanine | yes | rectangle | 140.694 | 130.005 | 50 | 0.435529 | 130.005 | 180.436 | HAUT Mezzanine (Couverture 2134) | -99.6977 | Mezzanine (Mezzanine 49003) | 140.7 | 140.7 | 130 | 130 | 800 | 800 | 18300 | 110000 | Chêne | 109745 | 109745 | 130.005 | 844.163 | 18290.9 | 18290.9 | ...de matériaux et couleurs = Chêne; ...de stratigraphies = default; ...de matériaux et couleurs - 1 = Chêne; ...de matériaux et couleurs - 2 = Chêne

# IfcWallStandardCase: default 600, Enveloppe 163723
In: Niveau 2
Type - Material: <aucun> 60 cm
Description: Enveloppe; Group: ...de stratigraphies = default; ...de matériaux et couleurs = Ivoire clair; ...de matériaux et couleurs - 1 = Ivoire clair; ...de matériaux et couleurs - 2 = Ivoire clair
__RECOGNIZE__ - ID: 163723; TPLG: 366; TPLG_OD: 9000; GENERATE: 1
CTLG_EXTERNAL_LINK - 0, DocType: 2; 0, Tag: 0; 0, Crc: 1977773087; 1, DocType: 2; 1, Tag: 100; 1, Crc: 1977773087; 2, DocType: 2; 2, Tag: 200; 2, Crc: 1977773087; 3, DocType: 9; 3, Tag: 0; 3, Crc: 701806286
IFC_PSET_PolygonOffset - polygonOffsetFactor: 2; polygonOffsetUnits: 2
IFC_Pset_Alignment - Alignment: 1
IFC_Pset_Strat_Detail_Align - ExternalFace: 0
IFC_Pset_Caractéristiques - ID: 163723; Numérotation: 0391; Numéro niveau: 05; Titre niveau: Niveau 2; Stratigraphie: default [600,00]; Épaisseur: 60 cm; Épaisseur VARIABLE: yes
IFC_Pset_Caractéristiques_FRUIT - Fruit: no; Taille: 0 cm
IFC_Pset_Géométrie - Forme en Élévation: rectangle; Longueur: 92.6246 cm; Hauteur: 235 cm; Cote: 1.06581e-12 cm
IFC_Pset_Géométrie_P1 (POINT initial) - Hauteur: 235 cm; Cote: 1.06581e-12 cm; Angle XY: 90.6789 deg
IFC_Pset_Géométrie_P2 (POINT final) - Hauteur: 235 cm; Cote: 1.06581e-12 cm; Angle XY: 270.679 deg
IFC_Pset_Système de Référence Altimétrique_SUPÉRIEUR - NIVEAU: HAUT Niveau 2 (Mezzanine 49003); delta: 0 cm; delta (P1): 0 cm; delta (P2): 0 cm; sous Niveau: <aucun>
IFC_Pset_Système de Référence Altimétrique_INFÉRIEUR - NIVEAU: Niveau 2 (Niveau 2 13545); delta: 1.06581e-12 cm; delta (P1): 1.06581e-12 cm; delta (P2): 1.06581e-12 cm; sous Niveau: <aucun>
IFC_Pset_Données Métré - Longueur Pied: 92.6 cm; Longueur Tête: 92.6 cm; Hauteur Maximale: 235 cm; Hauteur Minimale: 235 cm; Surface en Plan: 5800 cm2; Surface Pied: 5800 cm2; Surface Tête: 5800 cm2; Surface de la Paroi: 21800 cm2; Volume: 1370000 cm3
IFC_Pset_Matériaux - Face gauche: Ivoire clair; Face droite: Ivoire clair; Face latérale: Ivoire clair
Pset_WallCommon - Reference: default [600,00] (..\VERTICALES\Default\)
BaseQuantities - GrossVolume: 1363805 cm3; NetVolume: 1363805 cm3; NominalLength: 92.6246 cm; NominalWidth: 62.6554 cm; NominalHeight: 235 cm; GrossFootprintArea: 5803.43 cm2; NetFootprintArea: 5803.43 cm2; GrossSideArea: 21766.8 cm2; NetSideArea: 21766.8 cm2

# IfcWallStandardCase: default 603.693237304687, Enveloppe 150762
In: Niveau 2
Type - Material: <aucun> 60.3693 cm
Description: Enveloppe; Group: ...de stratigraphies = default; ...de matériaux et couleurs = Ivoire clair; ...de matériaux et couleurs - 1 = Ivoire clair; ...de matériaux et couleurs - 2 = Ivoire clair
__RECOGNIZE__ - ID: 150762; TPLG: 366; TPLG_OD: 9000; GENERATE: 1
CTLG_EXTERNAL_LINK - 0, DocType: 2; 0, Tag: 0; 0, Crc: 1977773087; 1, DocType: 2; 1, Tag: 100; 1, Crc: 1977773087; 2, DocType: 2; 2, Tag: 200; 2, Crc: 1977773087; 3, DocType: 9; 3, Tag: 0; 3, Crc: 1111379316
IFC_PSET_PolygonOffset - polygonOffsetFactor: 2; polygonOffsetUnits: 2
IFC_Pset_Alignment - Alignment: 1
IFC_Pset_Strat_Detail_Align - ExternalFace: 0
IFC_Pset_Caractéristiques - ID: 150762; Numérotation: 0339; Numéro niveau: 05; Titre niveau: Niveau 2; Stratigraphie: default [603,69]; Épaisseur: 60.37 cm; Épaisseur VARIABLE: no
IFC_Pset_Caractéristiques_FRUIT - Fruit: no; Taille: 0 cm
IFC_Pset_Géométrie - Forme en Élévation: rectangle; Longueur: 72.6805 cm; Hauteur: 240 cm; Cote: 1.42109e-12 cm
IFC_Pset_Géométrie_P1 (POINT initial) - Hauteur: 240 cm; Cote: 1.42109e-12 cm; Angle XY: 89.6756 deg
IFC_Pset_Géométrie_P2 (POINT final) - Hauteur: 240 cm; Cote: 1.42109e-12 cm; Angle XY: 269.676 deg
IFC_Pset_Système de Référence Altimétrique_SUPÉRIEUR - NIVEAU: HAUT Niveau 2 (Mezzanine 49003); delta: 5 cm; delta (P1): 5 cm; delta (P2): 5 cm; sous Niveau: <aucun>
IFC_Pset_Système de Référence Altimétrique_INFÉRIEUR - NIVEAU: Niveau 2 (Niveau 2 13545); delta: 1.42109e-12 cm; delta (P1): 1.42109e-12 cm; delta (P2): 1.42109e-12 cm; sous Niveau: <aucun>
IFC_Pset_Données Métré - Longueur Pied: 72.7 cm; Longueur Tête: 72.7 cm; Hauteur Maximale: 240 cm; Hauteur Minimale: 240 cm; Surface en Plan: 4400 cm2; Surface Pied: 4400 cm2; Surface Tête: 4400 cm2; Surface de la Paroi: 17400 cm2; Volume: 1040000 cm3
IFC_Pset_Matériaux - Face gauche: Ivoire clair; Face droite: Ivoire clair; Face latérale: Ivoire clair
Pset_WallCommon - Reference: default [603,69] (..\VERTICALES\Default\)
BaseQuantities - GrossVolume: 1053041 cm3; NetVolume: 1053041 cm3; NominalLength: 72.6805 cm; NominalWidth: 60.3693 cm; NominalHeight: 240 cm; GrossFootprintArea: 4387.67 cm2; NetFootprintArea: 4387.67 cm2; GrossSideArea: 17443.3 cm2; NetSideArea: 17443.3 cm2

# IfcWallStandardCase: default 610 (2)
Type - Material: <aucun> 61 cm
Description: Enveloppe; Group: ...de stratigraphies = default; ...de matériaux et couleurs = Ivoire clair; ...de matériaux et couleurs - 1 = Ivoire clair; ...de matériaux et couleurs - 2 = Ivoire clair
__RECOGNIZE__ - TPLG: 366; TPLG_OD: 9000; GENERATE: 1
CTLG_EXTERNAL_LINK - 0, DocType: 2; 0, Tag: 0; 0, Crc: 1977773087; 1, DocType: 2; 1, Tag: 100; 1, Crc: 1977773087; 2, DocType: 2; 2, Tag: 200; 2, Crc: 1977773087; 3, DocType: 9; 3, Tag: 0; 3, Crc: 323357256
IFC_PSET_PolygonOffset - polygonOffsetFactor: 2; polygonOffsetUnits: 2
IFC_Pset_Strat_Detail_Align - ExternalFace: 0
IFC_Pset_Caractéristiques - Stratigraphie: default [610,00]; Épaisseur: 61 cm
IFC_Pset_Caractéristiques_FRUIT - Fruit: no; Taille: 0 cm
IFC_Pset_Géométrie - Forme en Élévation: rectangle; Cote: 0.0128504 cm
IFC_Pset_Géométrie_P1 (POINT initial) - Cote: 0.0128504 cm
IFC_Pset_Géométrie_P2 (POINT final) - Cote: 0.0128504 cm
IFC_Pset_Système de Référence Altimétrique_SUPÉRIEUR - sous Niveau: <aucun>
IFC_Pset_Système de Référence Altimétrique_INFÉRIEUR - delta: 0.0128504 cm; delta (P1): 0.0128504 cm; delta (P2): 0.0128504 cm; sous Niveau: <aucun>
IFC_Pset_Matériaux - Face gauche: Ivoire clair; Face droite: Ivoire clair; Face latérale: Ivoire clair
Pset_WallCommon - Reference: default [610,00] (..\VERTICALES\Default\)
Name | In | __RECOGNIZE__, ID = IFC_Pset_Caractéristiques, ID | Alignment | Numérotation | Numéro niveau | Titre niveau | Épaisseur VARIABLE | Longueur (cm) = NominalLength (cm) | IFC_Pset_Géométrie, Hauteur (cm) = IFC_Pset_Géométrie_P1 (POINT initial), Hauteur (cm) = IFC_Pset_Géométrie_P2 (POINT final), Hauteur (cm) = NominalHeight (cm) | IFC_Pset_Géométrie_P1 (POINT initial), Angle XY (deg) | IFC_Pset_Géométrie_P2 (POINT final), Angle XY (deg) | IFC_Pset_Système de Référence Altimétrique_SUPÉRIEUR, NIVEAU | delta (cm) = delta (P1) (cm) = delta (P2) (cm) | IFC_Pset_Système de Référence Altimétrique_INFÉRIEUR, NIVEAU | Longueur Pied (cm) = Longueur Tête (cm) | Hauteur Maximale (cm) = Hauteur Minimale (cm) | Surface en Plan (cm2) = Surface Pied (cm2) = Surface Tête (cm2) | Surface de la Paroi (cm2) | Volume (cm3) | GrossVolume (cm3) = NetVolume (cm3) | NominalWidth (cm) | GrossFootprintArea (cm2) = NetFootprintArea (cm2) | GrossSideArea (cm2) = NetSideArea (cm2)
Enveloppe 2661 | Rez-de-chaussée | 2661 | 1 | 0008 | 03 | Rez-de-chaussée | yes | 387.664 | 399.097 | 90.4996 | 270.5 | HAUT Rez-de-chaussée (Niveau 1 2343) | -78.6853 | Rez-de-chaussée (Rez-de-chaussée 1047) | 387.7 | 399.1 | 24200 | 154700 | 9590000 | 9659103 | 62.4314 | 24202.4 | 154716
Enveloppe 93300 | Niveau 1 | 93300 | 0 | 0203 | 04 | Niveau 1 | no | 240.709 | 376.102 | 0.120163 | 180.12 | HAUT Niveau 1 (Niveau 2 13545) | 0 | Niveau 1 (Niveau 1 2343) | 240.7 | 376.1 | 14700 | 90500 | 5520000 | 5522408 | 61 | 14683.3 | 90531.3

# IfcWallStandardCase: default 615 (2)
In: Niveau 2
Type - Material: <aucun> 61.5 cm
Description: Enveloppe; Group: ...de stratigraphies = default; ...de matériaux et couleurs = Ivoire clair; ...de matériaux et couleurs - 1 = Ivoire clair; ...de matériaux et couleurs - 2 = Ivoire clair
__RECOGNIZE__ - TPLG: 366; TPLG_OD: 9000; GENERATE: 1
CTLG_EXTERNAL_LINK - 0, DocType: 2; 0, Tag: 0; 0, Crc: 1977773087; 1, DocType: 2; 1, Tag: 100; 1, Crc: 1977773087; 2, DocType: 2; 2, Tag: 200; 2, Crc: 1977773087; 3, DocType: 9; 3, Tag: 0; 3, Crc: -678832140
IFC_PSET_PolygonOffset - polygonOffsetFactor: 2; polygonOffsetUnits: 2
IFC_Pset_Alignment - Alignment: 1
IFC_Pset_Strat_Detail_Align - ExternalFace: 0
IFC_Pset_Caractéristiques - Numéro niveau: 05; Titre niveau: Niveau 2; Stratigraphie: default [615,00]; Épaisseur: 61.5 cm; Épaisseur VARIABLE: no
IFC_Pset_Caractéristiques_FRUIT - Fruit: no; Taille: 0 cm
IFC_Pset_Géométrie - Forme en Élévation: rectangle; Hauteur: 334.702 cm; Cote: 1.42109e-12 cm
IFC_Pset_Géométrie_P1 (POINT initial) - Hauteur: 334.702 cm; Cote: 1.42109e-12 cm
IFC_Pset_Géométrie_P2 (POINT final) - Hauteur: 334.702 cm; Cote: 1.42109e-12 cm
IFC_Pset_Système de Référence Altimétrique_SUPÉRIEUR - NIVEAU: HAUT Mezzanine (Couverture 2134); delta: -180 cm; delta (P1): -180 cm; delta (P2): -180 cm; sous Niveau: <aucun>
IFC_Pset_Système de Référence Altimétrique_INFÉRIEUR - NIVEAU: Niveau 2 (Niveau 2 13545); delta: 1.42109e-12 cm; delta (P1): 1.42109e-12 cm; delta (P2): 1.42109e-12 cm; sous Niveau: <aucun>
IFC_Pset_Données Métré - Hauteur Maximale: 334.7 cm; Hauteur Minimale: 334.7 cm
IFC_Pset_Matériaux - Face gauche: Ivoire clair; Face droite: Ivoire clair; Face latérale: Ivoire clair
Pset_WallCommon - Reference: default [615,00] (..\VERTICALES\Default\)
BaseQuantities - NominalWidth: 61.5 cm; NominalHeight: 334.702 cm
Name | __RECOGNIZE__, ID = IFC_Pset_Caractéristiques, ID | Numérotation | Longueur (cm) = NominalLength (cm) | IFC_Pset_Géométrie_P1 (POINT initial), Angle XY (deg) | IFC_Pset_Géométrie_P2 (POINT final), Angle XY (deg) | Longueur Pied (cm) = Longueur Tête (cm) | Surface en Plan (cm2) = Surface Pied (cm2) = Surface Tête (cm2) | Surface de la Paroi (cm2) | Volume (cm3) | GrossVolume (cm3) | NetVolume (cm3) | GrossFootprintArea (cm2) = NetFootprintArea (cm2) | GrossSideArea (cm2) | NetSideArea (cm2)
Enveloppe 168083 | 168083 | 0412 | 20.4037 | 91.3079 | 271.308 | 20.4 | 1300 | 6800 | 420000 | 419994 | 419994 | 1254.83 | 6829.16 | 6829.16
Enveloppe 168119 | 168119 | 0413 | 96.3831 | 90.6576 | 270.658 | 96.4 | 6000 | 32300 | 2000000 | 1983969 | 744136 | 5927.56 | 32259.7 | 12099.8

# IfcWallStandardCase: default 62, Enveloppe 93406
In: Niveau 1
Type - Material: <aucun> 6.2 cm
Description: Enveloppe; Group: ...de stratigraphies = default; ...de matériaux et couleurs = Ivoire clair; ...de matériaux et couleurs - 1 = Ivoire clair; ...de matériaux et couleurs - 2 = Ivoire clair
__RECOGNIZE__ - ID: 93406; TPLG: 366; TPLG_OD: 9000; GENERATE: 1
CTLG_EXTERNAL_LINK - 0, DocType: 2; 0, Tag: 0; 0, Crc: 1977773087; 1, DocType: 2; 1, Tag: 100; 1, Crc: 1977773087; 2, DocType: 2; 2, Tag: 200; 2, Crc: 1977773087; 3, DocType: 9; 3, Tag: 0; 3, Crc: -360660328
IFC_PSET_PolygonOffset - polygonOffsetFactor: 2; polygonOffsetUnits: 2
IFC_Pset_Alignment - Alignment: 0
IFC_Pset_Strat_Detail_Align - ExternalFace: 0
IFC_Pset_Caractéristiques - ID: 93406; Numérotation: 0206; Numéro niveau: 04; Titre niveau: Niveau 1; Stratigraphie: default [62,00]; Épaisseur: 6.2 cm; Épaisseur VARIABLE: no
IFC_Pset_Caractéristiques_FRUIT - Fruit: no; Taille: 0 cm
IFC_Pset_Géométrie - Forme en Élévation: rectangle; Longueur: 67.7982 cm; Hauteur: 376.102 cm; Cote: 0.0128504 cm
IFC_Pset_Géométrie_P1 (POINT initial) - Hauteur: 376.102 cm; Cote: 0.0128504 cm; Angle XY: 90.7713 deg
IFC_Pset_Géométrie_P2 (POINT final) - Hauteur: 376.102 cm; Cote: 0.0128504 cm; Angle XY: 270.771 deg
IFC_Pset_Système de Référence Altimétrique_SUPÉRIEUR - NIVEAU: HAUT Niveau 1 (Niveau 2 13545); delta: 0 cm; delta (P1): 0 cm; delta (P2): 0 cm; sous Niveau: <aucun>
IFC_Pset_Système de Référence Altimétrique_INFÉRIEUR - NIVEAU: Niveau 1 (Niveau 1 2343); delta: 0.0128504 cm; delta (P1): 0.0128504 cm; delta (P2): 0.0128504 cm; sous Niveau: <aucun>
IFC_Pset_Données Métré - Longueur Pied: 67.8 cm; Longueur Tête: 67.8 cm; Hauteur Maximale: 376.1 cm; Hauteur Minimale: 376.1 cm; Surface en Plan: 400 cm2; Surface Pied: 400 cm2; Surface Tête: 400 cm2; Surface de la Paroi: 25500 cm2; Volume: 150000 cm3
IFC_Pset_Matériaux - Face gauche: Ivoire clair; Face droite: Ivoire clair; Face latérale: Ivoire clair
Pset_WallCommon - Reference: default [62,00] (..\VERTICALES\Default\)
BaseQuantities - GrossVolume: 158094 cm3; NetVolume: 158094 cm3; NominalLength: 67.7982 cm; NominalWidth: 6.2 cm; NominalHeight: 376.102 cm; GrossFootprintArea: 420.349 cm2; NetFootprintArea: 420.349 cm2; GrossSideArea: 25499.1 cm2; NetSideArea: 25499.1 cm2

# IfcWallStandardCase: default 62.5682640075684, Enveloppe 3415
In: Rez-de-chaussée
Type - Material: <aucun> 6.25683 cm
Description: Enveloppe; Group: ...de stratigraphies = default; ...de matériaux et couleurs = Ivoire clair; ...de matériaux et couleurs - 1 = Ivoire clair; ...de matériaux et couleurs - 2 = Ivoire clair
__RECOGNIZE__ - ID: 3415; TPLG: 366; TPLG_OD: 9000; GENERATE: 1
CTLG_EXTERNAL_LINK - 0, DocType: 2; 0, Tag: 0; 0, Crc: 1977773087; 1, DocType: 2; 1, Tag: 100; 1, Crc: 1977773087; 2, DocType: 2; 2, Tag: 200; 2, Crc: 1977773087; 3, DocType: 9; 3, Tag: 0; 3, Crc: -1844175474
IFC_PSET_PolygonOffset - polygonOffsetFactor: 2; polygonOffsetUnits: 2
IFC_Pset_Alignment - Alignment: 0
IFC_Pset_Strat_Detail_Align - ExternalFace: 0
IFC_Pset_Caractéristiques - ID: 3415; Numérotation: 0029; Numéro niveau: 03; Titre niveau: Rez-de-chaussée; Stratigraphie: default [62,57]; Épaisseur: 6.26 cm; Épaisseur VARIABLE: no
IFC_Pset_Caractéristiques_FRUIT - Fruit: no; Taille: 0 cm
IFC_Pset_Géométrie - Forme en Élévation: rectangle; Longueur: 149.353 cm; Hauteur: 391.395 cm; Cote: 0.0128504 cm
IFC_Pset_Géométrie_P1 (POINT initial) - Hauteur: 391.395 cm; Cote: 0.0128504 cm; Angle XY: 0.0800045 deg
IFC_Pset_Géométrie_P2 (POINT final) - Hauteur: 391.395 cm; Cote: 0.0128504 cm; Angle XY: 180.08 deg
IFC_Pset_Système de Référence Altimétrique_SUPÉRIEUR - NIVEAU: HAUT Rez-de-chaussée (Niveau 1 2343); delta: -86.3871 cm; delta (P1): -86.3871 cm; delta (P2): -86.3871 cm; sous Niveau: <aucun>
IFC_Pset_Système de Référence Altimétrique_INFÉRIEUR - NIVEAU: Rez-de-chaussée (Rez-de-chaussée 1047); delta: 0.0128504 cm; delta (P1): 0.0128504 cm; delta (P2): 0.0128504 cm; sous Niveau: <aucun>
IFC_Pset_Données Métré - Longueur Pied: 149.4 cm; Longueur Tête: 149.4 cm; Hauteur Maximale: 391.4 cm; Hauteur Minimale: 391.4 cm; Surface en Plan: 900 cm2; Surface Pied: 900 cm2; Surface Tête: 900 cm2; Surface de la Paroi: 58500 cm2; Volume: 350000 cm3
IFC_Pset_Matériaux - Face gauche: Ivoire clair; Face droite: Ivoire clair; Face latérale: Ivoire clair
Pset_WallCommon - Reference: default [62,57] (..\VERTICALES\Default\)
BaseQuantities - GrossVolume: 365749 cm3; NetVolume: 365749 cm3; NominalLength: 149.353 cm; NominalWidth: 6.25683 cm; NominalHeight: 391.395 cm; GrossFootprintArea: 934.474 cm2; NetFootprintArea: 934.474 cm2; GrossSideArea: 58456 cm2; NetSideArea: 58456 cm2

# IfcWallStandardCase: default 620 (21)
Type - Material: <aucun> 62 cm
__RECOGNIZE__ - GENERATE: 1
CTLG_EXTERNAL_LINK - 0, DocType: 2; 0, Tag: 0; 1, DocType: 2; 1, Tag: 100; 2, DocType: 2; 2, Tag: 200; 3, DocType: 9; 3, Tag: 0; 3, Crc: -230943540
IFC_PSET_PolygonOffset - polygonOffsetFactor: 2; polygonOffsetUnits: 2
IFC_Pset_Caractéristiques - Stratigraphie: default [620,00]; Épaisseur: 62 cm
IFC_Pset_Caractéristiques_FRUIT - Fruit: no; Taille: 0 cm
IFC_Pset_Géométrie - Forme en Élévation: rectangle
IFC_Pset_Système de Référence Altimétrique_SUPÉRIEUR - sous Niveau: <aucun>
IFC_Pset_Système de Référence Altimétrique_INFÉRIEUR - sous Niveau: <aucun>
Pset_WallCommon - Reference: default [620,00] (..\VERTICALES\Default\)
Name | In | Description | __RECOGNIZE__, ID = IFC_Pset_Caractéristiques, ID | TPLG | TPLG_OD | 0, Crc = 1, Crc = 2, Crc | Alignment | ExternalFace | Numérotation | Numéro niveau | Titre niveau | Épaisseur VARIABLE | Longueur (cm) = NominalLength (cm) | IFC_Pset_Géométrie, Hauteur (cm) = IFC_Pset_Géométrie_P1 (POINT initial), Hauteur (cm) = IFC_Pset_Géométrie_P2 (POINT final), Hauteur (cm) = NominalHeight (cm) | IFC_Pset_Géométrie, Cote (cm) = IFC_Pset_Géométrie_P1 (POINT initial), Cote (cm) = IFC_Pset_Géométrie_P2 (POINT final), Cote (cm) = IFC_Pset_Système de Référence Altimétrique_INFÉRIEUR, delta (cm) = IFC_Pset_Système de Référence Altimétrique_INFÉRIEUR, delta (P1) (cm) = IFC_Pset_Système de Référence Altimétrique_INFÉRIEUR, delta (P2) (cm) | IFC_Pset_Géométrie_P1 (POINT initial), Angle XY (deg) | IFC_Pset_Géométrie_P2 (POINT final), Angle XY (deg) | IFC_Pset_Système de Référence Altimétrique_SUPÉRIEUR, NIVEAU | IFC_Pset_Système de Référence Altimétrique_SUPÉRIEUR, delta (cm) = IFC_Pset_Système de Référence Altimétrique_SUPÉRIEUR, delta (P1) (cm) = IFC_Pset_Système de Référence Altimétrique_SUPÉRIEUR, delta (P2) (cm) | IFC_Pset_Système de Référence Altimétrique_INFÉRIEUR, NIVEAU | Longueur Pied (cm) = Longueur Tête (cm) | Hauteur Maximale (cm) = Hauteur Minimale (cm) | Surface en Plan (cm2) | Surface Pied (cm2) = Surface Tête (cm2) | Surface de la Paroi (cm2) | Volume (cm3) | Face gauche = Face droite = Face latérale | GrossVolume (cm3) | NetVolume (cm3) | NominalWidth (cm) | GrossFootprintArea (cm2) = NetFootprintArea (cm2) | GrossSideArea (cm2) | NetSideArea (cm2) | Group | Rayon (cm) | Point arc | Centre | Angle de la Tangente (deg)
Enveloppe 230407 | Rez-de-Jardin | Enveloppe | 230407 | 366 | 9000 | 1977773087 | 1 | 1 | 0522 | 02 | Rez-de-Jardin | no | 211.64 | 43.7 | -1.94511e-11 | 90.4317 | 270.432 | HAUT Rez-de-Jardin (Rez-de-chaussée 1047) | -247.7 | Rez-de-Jardin (Rez-de-Jardin 15545) | 211.6 | 43.7 | 13100 | 13100 | 9200 | 570000 | Ivoire clair | 573417 | 573417 | 62 | 13121.7 | 9248.67 | 9248.67 | ...de stratigraphies = default; ...de matériaux et couleurs = Ivoire clair; ...de matériaux et couleurs - 1 = Ivoire clair; ...de matériaux et couleurs - 2 = Ivoire clair
Enveloppe courbe 239181 | Rez-de-Jardin | Enveloppe courbe | 239181 | 367 | 9001 | -746779066 | 0 | 0 | 28 | 02 | Rez-de-Jardin | no | 220.41 | 43.7 | 0 | 37.4206 | 217.421 | HAUT Rez-de-Jardin (Rez-de-chaussée 1047) | -247.7 | Rez-de-Jardin (Rez-de-Jardin 15545) | 220.4 | 43.7 | 8700 | 13700 | 9600 | 600000 | Blanc | 596036 | 596036 | 61.8815 | 13639.3 | 9631.9 | 9631.9 | ...de matériaux et couleurs = Blanc; ...de matériaux et couleurs - 1 = Blanc; ...de matériaux et couleurs - 2 = Blanc; ...de stratigraphies = default | 337.476 | [1 328,0; -1 083,9] cm | [1 587,8; -822,6] cm | 35.9337
Enveloppe courbe 239018 | Rez-de-Jardin | Enveloppe courbe | 239018 | 367 | 9001 | -746779066 | 0 | 0 | 27 | 02 | Rez-de-Jardin | no | 106.393 | 43.7 | 0 | 13.1072 | 193.107 | HAUT Rez-de-Jardin (Rez-de-chaussée 1047) | -247.7 | Rez-de-Jardin (Rez-de-Jardin 15545) | 106.4 | 43.7 | 4200 | 6600 | 4700 | 290000 | Blanc | 287941 | 287941 | 61.9311 | 6589.03 | 4649.37 | 4649.37 | ...de matériaux et couleurs = Blanc; ...de matériaux et couleurs - 1 = Blanc; ...de matériaux et couleurs - 2 = Blanc; ...de stratigraphies = default | 465.079 | [1 244,0; -952,2] cm | [1 708,0; -776,8] cm | 23.777
Enveloppe courbe 234730 | Rez-de-Jardin | Enveloppe courbe | 234730 | 367 | 9001 | -746779066 | 0 | 0 | 26 | 02 | Rez-de-Jardin | no | 268.873 | 43.7 | 0 | 57.4172 | 237.417 | HAUT Rez-de-Jardin (Rez-de-chaussée 1047) | -247.7 | Rez-de-Jardin (Rez-de-Jardin 15545) | 268.9 | 43.7 | 10600 | 16700 | 11700 | 730000 | Blanc | 726816 | 726816 | 61.8581 | 16632 | 11749.7 | 11749.7 | ...de matériaux et couleurs = Blanc; ...de matériaux et couleurs - 1 = Blanc; ...de matériaux et couleurs - 2 = Blanc; ...de stratigraphies = default | 268.304 | [1 549,1; -1 794,8] cm | [1 354,2; -1 659,4] cm | 11.4852
Enveloppe courbe 239638 | Rez-de-Jardin | Enveloppe courbe | 239638 | 367 | 9001 | -746779066 | 0 | 0 | 29 | 02 | Rez-de-Jardin | no | 282.288 | 43.7 | 0 | 61.4637 | 241.464 | HAUT Rez-de-Jardin (Rez-de-chaussée 1047) | -247.7 | Rez-de-Jardin (Rez-de-Jardin 15545) | 282.2 | 43.7 | 11100 | 17500 | 12300 | 760000 | Blanc | 762823 | 762823 | 61.8372 | 17455.9 | 12336 | 12336 | ...de matériaux et couleurs = Blanc; ...de matériaux et couleurs - 1 = Blanc; ...de matériaux et couleurs - 2 = Blanc; ...de stratigraphies = default | 263.146 | [1 544,9; -1 240,9] cm | [1 356,7; -1 377,0] cm | 13.5084
Enveloppe courbe 233227 | Rez-de-Jardin | Enveloppe courbe | 233227 | 367 | 9001 | -746779066 | 1 | 0 | 22 | 02 | Rez-de-Jardin | no | 175.25 | 43.7 | 0 | 29.7954 | 209.795 | HAUT Rez-de-Jardin (Rez-de-chaussée 1047) | -247.7 | Rez-de-Jardin (Rez-de-Jardin 15545) | 175.2 | 43.7 | 6900 | 10900 | 7700 | 480000 | Blanc | 473954 | 473954 | 61.8864 | 10845.6 | 7658.44 | 7658.44 | ...de matériaux et couleurs = Blanc; ...de matériaux et couleurs - 1 = Blanc; ...de matériaux et couleurs - 2 = Blanc; ...de stratigraphies = default | 337.002 | [1 099,5; -1 634,5] cm | [797,5; -1 844,8] cm | 32.1211
Enveloppe courbe 232920 | Rez-de-Jardin | Enveloppe courbe | 232920 | 367 | 9001 | -746779066 | 1 | 0 | 21 | 02 | Rez-de-Jardin | no | 215.068 | 43.7 | 0 | 38.4826 | 218.483 | HAUT Rez-de-Jardin (Rez-de-chaussée 1047) | -247.7 | Rez-de-Jardin (Rez-de-Jardin 15545) | 215 | 43.7 | 8500 | 13300 | 9400 | 580000 | Blanc | 581621 | 581621 | 61.8846 | 13309.4 | 9398.47 | 9398.47 | ...de matériaux et couleurs = Blanc; ...de matériaux et couleurs - 1 = Blanc; ...de matériaux et couleurs - 2 = Blanc; ...de stratigraphies = default | 320.209 | [943,6; -1 506,9] cm | [806,1; -1 830,0] cm | 36.4648
Enveloppe courbe 232765 | Rez-de-Jardin | Enveloppe courbe | 232765 | 367 | 9001 | -746779066 | 0 | 0 | 20 | 02 | Rez-de-Jardin | no | 100.287 | 43.7 | 0 | 14.3044 | 194.304 | HAUT Rez-de-Jardin (Rez-de-chaussée 1047) | -247.7 | Rez-de-Jardin (Rez-de-Jardin 15545) | 100.3 | 43.7 | 4000 | 6200 | 4400 | 270000 | Blanc | 271379 | 271379 | 61.9231 | 6210.05 | 4382.52 | 4382.52 | ...de matériaux et couleurs = Blanc; ...de matériaux et couleurs - 1 = Blanc; ...de matériaux et couleurs - 2 = Blanc; ...de stratigraphies = default | 401.695 | [769,8; -1 480,8] cm | [809,5; -1 911,7] cm | 24.3756
Enveloppe courbe 234423 | Rez-de-Jardin | Enveloppe courbe | 234423 | 367 | 9001 | -746779066 | 0 | 0 | 25 | 02 | Rez-de-Jardin | no | 236.492 | 43.7 | 0 | 52.7701 | 232.77 | HAUT Rez-de-Jardin (Rez-de-chaussée 1047) | -247.7 | Rez-de-Jardin (Rez-de-Jardin 15545) | 236.5 | 43.7 | 9300 | 14700 | 10300 | 640000 | Blanc | 639173 | 639173 | 61.8474 | 14626.4 | 10334.7 | 10334.7 | ...de matériaux et couleurs = Blanc; ...de matériaux et couleurs - 1 = Blanc; ...de matériaux et couleurs - 2 = Blanc; ...de stratigraphies = default | 256.774 | [1 374,9; -1 893,4] cm | [1 362,5; -1 668,0] cm | 9.1616
Enveloppe courbe 234230 | Rez-de-Jardin | Enveloppe courbe | 234230 | 367 | 9001 | -746779066 | 1 | 0 | 24 | 02 | Rez-de-Jardin | no | 137.978 | 43.7 | 0 | 29.4513 | 209.451 | HAUT Rez-de-Jardin (Rez-de-chaussée 1047) | -247.7 | Rez-de-Jardin (Rez-de-Jardin 15545) | 138 | 43.7 | 5400 | 8600 | 6000 | 370000 | Blanc | 373049 | 373049 | 61.8691 | 8536.58 | 6029.64 | 6029.64 | ...de matériaux et couleurs = Blanc; ...de matériaux et couleurs - 1 = Blanc; ...de matériaux et couleurs - 2 = Blanc; ...de stratigraphies = default | 268.428 | [1 219,0; -1 841,2] cm | [1 371,5; -1 659,2] cm | 2.49777
Enveloppe courbe 233687 | Rez-de-Jardin | Enveloppe courbe | 233687 | 367 | 9001 | -746779066 | 1 | 0 | 23 | 02 | Rez-de-Jardin | no | 98.1722 | 43.7 | 0 | 20.7496 | 200.75 | HAUT Rez-de-Jardin (Rez-de-chaussée 1047) | -247.7 | Rez-de-Jardin (Rez-de-Jardin 15545) | 98.2 | 43.7 | 3900 | 6100 | 4300 | 270000 | Blanc | 265479 | 265479 | 61.8814 | 6075.03 | 4290.12 | 4290.12 | ...de matériaux et couleurs = Blanc; ...de matériaux et couleurs - 1 = Blanc; ...de matériaux et couleurs - 2 = Blanc; ...de stratigraphies = default | 271.083 | [1 169,1; -1 782,7] cm | [1 376,6; -1 662,0] cm | 6.84866
Enveloppe courbe 231997 | Rez-de-Jardin | Enveloppe courbe | 231997 | 367 | 9001 | -746779066 | 1 | 0 | 16 | 02 | Rez-de-Jardin | no | 81.0343 | 43.7 | 0 | 17.7018 | 197.702 | HAUT Rez-de-Jardin (Rez-de-chaussée 1047) | -247.7 | Rez-de-Jardin (Rez-de-Jardin 15545) | 81.1 | 43.7 | 3200 | 5000 | 3500 | 220000 | Blanc | 219095 | 219095 | 61.8702 | 5013.6 | 3541.2 | 3541.2 | ...de matériaux et couleurs = Blanc; ...de matériaux et couleurs - 1 = Blanc; ...de matériaux et couleurs - 2 = Blanc; ...de stratigraphies = default | 262.285 | [313,9; -1 381,3] cm | [533,6; -1 308,9] cm | 8.37254
Enveloppe courbe 231802 | Rez-de-Jardin | Enveloppe courbe | 231802 | 367 | 9001 | -746779066 | 1 | 0 | 15 | 02 | Rez-de-Jardin | no | 94.6462 | 43.7 | 0 | 12.5543 | 192.554 | HAUT Rez-de-Jardin (Rez-de-chaussée 1047) | -247.7 | Rez-de-Jardin (Rez-de-Jardin 15545) | 94.6 | 43.7 | 3700 | 5900 | 4100 | 250000 | Blanc | 256141 | 256141 | 61.9291 | 5861.35 | 4136.04 | 4136.04 | ...de matériaux et couleurs = Blanc; ...de matériaux et couleurs - 1 = Blanc; ...de matériaux et couleurs - 2 = Blanc; ...de stratigraphies = default | 431.949 | [304,4; -1 315,6] cm | [705,2; -1 304,6] cm | 10.9463
Enveloppe courbe 232610 | Rez-de-Jardin | Enveloppe courbe | 232610 | 367 | 9001 | -746779066 | 0 | 0 | 19 | 02 | Rez-de-Jardin | no | 90.482 | 43.7 | 0 | 15.9856 | 195.986 | HAUT Rez-de-Jardin (Rez-de-chaussée 1047) | -247.7 | Rez-de-Jardin (Rez-de-Jardin 15545) | 90.5 | 43.7 | 3600 | 5600 | 4000 | 250000 | Blanc | 244716 | 244716 | 61.8898 | 5599.91 | 3954.06 | 3954.06 | ...de matériaux et couleurs = Blanc; ...de matériaux et couleurs - 1 = Blanc; ...de matériaux et couleurs - 2 = Blanc; ...de stratigraphies = default | 324.307 | [669,1; -1 503,3] cm | [792,5; -1 836,5] cm | 25.2162
Enveloppe courbe 232417 | Rez-de-Jardin | Enveloppe courbe | 232417 | 367 | 9001 | -746779066 | 0 | 0 | 18 | 02 | Rez-de-Jardin | no | 152.35 | 43.7 | 0 | 33.4516 | 213.452 | HAUT Rez-de-Jardin (Rez-de-chaussée 1047) | -247.7 | Rez-de-Jardin (Rez-de-Jardin 15545) | 152.3 | 43.7 | 6000 | 9400 | 6700 | 420000 | Blanc | 411799 | 411799 | 61.8531 | 9423.32 | 6657.7 | 6657.7 | ...de matériaux et couleurs = Blanc; ...de matériaux et couleurs - 1 = Blanc; ...de matériaux et couleurs - 2 = Blanc; ...de stratigraphies = default | 260.945 | [555,2; -1 541,7] cm | [534,4; -1 312,7] cm | 0.497644
Enveloppe courbe 232112 | Rez-de-Jardin | Enveloppe courbe | 232112 | 367 | 9001 | -746779066 | 1 | 0 | 17 | 02 | Rez-de-Jardin | no | 228.845 | 43.7 | 0 | 49.5358 | 229.536 | HAUT Rez-de-Jardin (Rez-de-chaussée 1047) | -247.7 | Rez-de-Jardin (Rez-de-Jardin 15545) | 228.9 | 43.7 | 9000 | 14200 | 10000 | 620000 | Blanc | 618622 | 618622 | 61.8589 | 14156.1 | 10000.5 | 10000.5 | ...de matériaux et couleurs = Blanc; ...de matériaux et couleurs - 1 = Blanc; ...de matériaux et couleurs - 2 = Blanc; ...de stratigraphies = default | 264.694 | [387,9; -1 489,6] cm | [536,5; -1 309,3] cm | 7.54449
Enveloppe 94845 | Niveau 1 | Enveloppe | 94845 | 366 | 9000 | 1977773087 | 0 | 0 | 0239 | 04 | Niveau 1 | no | 242.912 | 376.102 | 0.0128504 | 179.777 | 359.777 | HAUT Niveau 1 (Niveau 2 13545) | 0 | Niveau 1 (Niveau 1 2343) | 242.9 | 376.1 | 15100 | 15100 | 91400 | 5670000 | Ivoire clair | 5664307 | 5664307 | 62 | 15060.6 | 91359.8 | 91359.8 | ...de stratigraphies = default; ...de matériaux et couleurs = Ivoire clair; ...de matériaux et couleurs - 1 = Ivoire clair; ...de matériaux et couleurs - 2 = Ivoire clair
Enveloppe 95008 | Niveau 1 | Enveloppe | 95008 | 366 | 9000 | 1977773087 | 0 | 0 | 0243 | 04 | Niveau 1 | no | 54.0298 | 376.102 | 0.0128504 | 0.649835 | 180.65 | HAUT Niveau 1 (Niveau 2 13545) | 0 | Niveau 1 (Niveau 1 2343) | 54 | 376.1 | 3300 | 3300 | 20300 | 1260000 | Ivoire clair | 1259885 | 1259885 | 62 | 3349.85 | 20320.7 | 20320.7 | ...de stratigraphies = default; ...de matériaux et couleurs = Ivoire clair; ...de matériaux et couleurs - 1 = Ivoire clair; ...de matériaux et couleurs - 2 = Ivoire clair
Enveloppe 177519 | Niveau 2 | Enveloppe | 177519 | 366 | 9000 | 1977773087 | 1 | 0 | 0458 | 05 | Niveau 2 | yes | 111.793 | 235 | 1.42109e-12 | 91.239 | 271.239 | HAUT Niveau 2 (Mezzanine 49003) | 0 | Niveau 2 (Niveau 2 13545) | 111.8 | 235 | 6900 | 6900 | 26300 | 1630000 | Ivoire clair | 1628822 | 409364 | 62 | 6931.16 | 26271.3 | 6602.64 | ...de stratigraphies = default; ...de matériaux et couleurs = Ivoire clair; ...de matériaux et couleurs - 1 = Ivoire clair; ...de matériaux et couleurs - 2 = Ivoire clair
Enveloppe 151022 | Niveau 2 | Enveloppe | 151022 | 366 | 9000 | 1977773087 | 0 | 0 | 0346 | 05 | Niveau 2 | yes | 128.775 | 235 | 1.42109e-12 | 89.6976 | 269.698 | HAUT Niveau 2 (Mezzanine 49003) | 0 | Niveau 2 (Niveau 2 13545) | 128.8 | 235 | 8100 | 8100 | 30300 | 1910000 | Ivoire clair | 1893857 | 1893857 | 62.5817 | 8058.96 | 30262.2 | 30262.2 | ...de stratigraphies = default; ...de matériaux et couleurs = Ivoire clair; ...de matériaux et couleurs - 1 = Ivoire clair; ...de matériaux et couleurs - 2 = Ivoire clair
Enveloppe 171080 | Niveau 2 | Enveloppe | 171080 | 366 | 9000 | 1977773087 | 0 | 0 | 0431 | 05 | Niveau 2 | no | 45.1426 | 247.5 | 1.42109e-12 | 1.47357 | 181.474 | HAUT Niveau 2 (Mezzanine 49003) | 12.5 | Niveau 2 (Niveau 2 13545) | 45.1 | 247.5 | 2800 | 2800 | 11200 | 690000 | Ivoire clair | 692714 | 692714 | 62 | 2798.84 | 11172.8 | 11172.8 | ...de stratigraphies = default; ...de matériaux et couleurs = Ivoire clair; ...de matériaux et couleurs - 1 = Ivoire clair; ...de matériaux et couleurs - 2 = Ivoire clair

# IfcWallStandardCase: default 621, Enveloppe 41159
In: Rez-de-chaussée
Type - Material: <aucun> 62.1 cm
Description: Enveloppe; Group: ...de stratigraphies = default; ...de matériaux et couleurs = Ivoire clair; ...de matériaux et couleurs - 1 = Ivoire clair; ...de matériaux et couleurs - 2 = Ivoire clair
__RECOGNIZE__ - ID: 41159; TPLG: 366; TPLG_OD: 9000; GENERATE: 1
CTLG_EXTERNAL_LINK - 0, DocType: 2; 0, Tag: 0; 0, Crc: 1977773087; 1, DocType: 2; 1, Tag: 100; 1, Crc: 1977773087; 2, DocType: 2; 2, Tag: 200; 2, Crc: 1977773087; 3, DocType: 9; 3, Tag: 0; 3, Crc: 729375987
IFC_PSET_PolygonOffset - polygonOffsetFactor: 2; polygonOffsetUnits: 2
IFC_Pset_Alignment - Alignment: 1
IFC_Pset_Strat_Detail_Align - ExternalFace: 0
IFC_Pset_Caractéristiques - ID: 41159; Numérotation: 0069; Numéro niveau: 03; Titre niveau: Rez-de-chaussée; Stratigraphie: default [621,00]; Épaisseur: 62.1 cm; Épaisseur VARIABLE: no
IFC_Pset_Caractéristiques_FRUIT - Fruit: no; Taille: 0 cm
IFC_Pset_Géométrie - Forme en Élévation: rectangle; Longueur: 39.0434 cm; Hauteur: 393.395 cm; Cote: 0.0128504 cm
IFC_Pset_Géométrie_P1 (POINT initial) - Hauteur: 393.395 cm; Cote: 0.0128504 cm; Angle XY: 89.6756 deg
IFC_Pset_Géométrie_P2 (POINT final) - Hauteur: 393.395 cm; Cote: 0.0128504 cm; Angle XY: 269.676 deg
IFC_Pset_Système de Référence Altimétrique_SUPÉRIEUR - NIVEAU: HAUT Rez-de-chaussée (Niveau 1 2343); delta: -84.3871 cm; delta (P1): -84.3871 cm; delta (P2): -84.3871 cm; sous Niveau: <aucun>
IFC_Pset_Système de Référence Altimétrique_INFÉRIEUR - NIVEAU: Rez-de-chaussée (Rez-de-chaussée 1047); delta: 0.0128504 cm; delta (P1): 0.0128504 cm; delta (P2): 0.0128504 cm; sous Niveau: <aucun>
IFC_Pset_Données Métré - Longueur Pied: 39 cm; Longueur Tête: 39 cm; Hauteur Maximale: 393.4 cm; Hauteur Minimale: 393.4 cm; Surface en Plan: 2400 cm2; Surface Pied: 2400 cm2; Surface Tête: 2400 cm2; Surface de la Paroi: 15300 cm2; Volume: 950000 cm3
IFC_Pset_Matériaux - Face gauche: Ivoire clair; Face droite: Ivoire clair; Face latérale: Ivoire clair
Pset_WallCommon - Reference: default [621,00] (..\VERTICALES\Default\)
BaseQuantities - GrossVolume: 953824 cm3; NetVolume: 953824 cm3; NominalLength: 39.0434 cm; NominalWidth: 62.1 cm; NominalHeight: 393.395 cm; GrossFootprintArea: 2424.59 cm2; NetFootprintArea: 2424.59 cm2; GrossSideArea: 15359.5 cm2; NetSideArea: 15359.5 cm2

# IfcWallStandardCase: default 625, Enveloppe 167088
In: Niveau 2
Type - Material: <aucun> 62.5 cm
Description: Enveloppe; Group: ...de stratigraphies = default; ...de matériaux et couleurs = Ivoire clair; ...de matériaux et couleurs - 1 = Ivoire clair; ...de matériaux et couleurs - 2 = Ivoire clair
__RECOGNIZE__ - ID: 167088; TPLG: 366; TPLG_OD: 9000; GENERATE: 1
CTLG_EXTERNAL_LINK - 0, DocType: 2; 0, Tag: 0; 0, Crc: 1977773087; 1, DocType: 2; 1, Tag: 100; 1, Crc: 1977773087; 2, DocType: 2; 2, Tag: 200; 2, Crc: 1977773087; 3, DocType: 9; 3, Tag: 0; 3, Crc: -1290092614
IFC_PSET_PolygonOffset - polygonOffsetFactor: 2; polygonOffsetUnits: 2
IFC_Pset_Alignment - Alignment: 0
IFC_Pset_Strat_Detail_Align - ExternalFace: 0
IFC_Pset_Caractéristiques - ID: 167088; Numérotation: 0410; Numéro niveau: 05; Titre niveau: Niveau 2; Stratigraphie: default [625,00]; Épaisseur: 62.5 cm; Épaisseur VARIABLE: no
IFC_Pset_Caractéristiques_FRUIT - Fruit: no; Taille: 0 cm
IFC_Pset_Géométrie - Forme en Élévation: trapèze; Longueur: 228.569 cm; Hauteur: 389.793 cm; Cote: 1.42109e-12 cm
IFC_Pset_Géométrie_P1 (POINT initial) - Hauteur: 389.793 cm; Cote: 1.42109e-12 cm; Angle XY: 90.6576 deg
IFC_Pset_Géométrie_P2 (POINT final) - Hauteur: 270.968 cm; Cote: 1.42109e-12 cm; Angle XY: 270.658 deg
IFC_Pset_Système de Référence Altimétrique_SUPÉRIEUR - NIVEAU: HAUT Mezzanine (Couverture 2134); delta: 0 cm; delta (P1): 0 cm; delta (P2): 0 cm; sous Niveau: Toit943674
IFC_Pset_Système de Référence Altimétrique_INFÉRIEUR - NIVEAU: Niveau 2 (Niveau 2 13545); delta: 1.42109e-12 cm; delta (P1): 1.42109e-12 cm; delta (P2): 1.42109e-12 cm; sous Niveau: <aucun>
IFC_Pset_Données Métré - Longueur Pied: 228.6 cm; Longueur Tête: 257.6 cm; Hauteur Maximale: 389.8 cm; Hauteur Minimale: 271 cm; Surface en Plan: 14300 cm2; Surface Pied: 14300 cm2; Surface Tête: 16100 cm2; Surface de la Paroi: 75500 cm2; Volume: 4680000 cm3
IFC_Pset_Matériaux - Face gauche: Ivoire clair; Face droite: Ivoire clair; Face latérale: Ivoire clair
Pset_WallCommon - Reference: default [625,00] (..\VERTICALES\Default\)
BaseQuantities - GrossVolume: 4719675 cm3; NetVolume: 4719675 cm3; NominalLength: 228.569 cm; NominalWidth: 62.5 cm; NominalHeight: 330.381 cm; GrossFootprintArea: 14285.6 cm2; NetFootprintArea: 14285.6 cm2; GrossSideArea: 75514.8 cm2; NetSideArea: 75514.8 cm2

# IfcWallStandardCase: default 627.069274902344 (2)
In: Rez-de-chaussée
Type - Material: <aucun> 62.7069 cm
Description: Enveloppe; Group: ...de stratigraphies = default; ...de matériaux et couleurs = Ivoire clair; ...de matériaux et couleurs - 1 = Ivoire clair; ...de matériaux et couleurs - 2 = Ivoire clair
__RECOGNIZE__ - TPLG: 366; TPLG_OD: 9000; GENERATE: 1
CTLG_EXTERNAL_LINK - 0, DocType: 2; 0, Tag: 0; 0, Crc: 1977773087; 1, DocType: 2; 1, Tag: 100; 1, Crc: 1977773087; 2, DocType: 2; 2, Tag: 200; 2, Crc: 1977773087; 3, DocType: 9; 3, Tag: 0; 3, Crc: 834410625
IFC_PSET_PolygonOffset - polygonOffsetFactor: 2; polygonOffsetUnits: 2
IFC_Pset_Alignment - Alignment: 1
IFC_Pset_Strat_Detail_Align - ExternalFace: 0
IFC_Pset_Caractéristiques - Numéro niveau: 03; Titre niveau: Rez-de-chaussée; Stratigraphie: default [627,07]; Épaisseur: 62.71 cm; Épaisseur VARIABLE: no
IFC_Pset_Caractéristiques_FRUIT - Fruit: no; Taille: 0 cm
IFC_Pset_Géométrie - Forme en Élévation: rectangle; Cote: 0.0128504 cm
IFC_Pset_Géométrie_P1 (POINT initial) - Cote: 0.0128504 cm; Angle XY: 179.777 deg
IFC_Pset_Géométrie_P2 (POINT final) - Cote: 0.0128504 cm; Angle XY: 359.777 deg
IFC_Pset_Système de Référence Altimétrique_SUPÉRIEUR - NIVEAU: HAUT Rez-de-chaussée (Niveau 1 2343); sous Niveau: <aucun>
IFC_Pset_Système de Référence Altimétrique_INFÉRIEUR - NIVEAU: Rez-de-chaussée (Rez-de-chaussée 1047); delta: 0.0128504 cm; delta (P1): 0.0128504 cm; delta (P2): 0.0128504 cm; sous Niveau: <aucun>
IFC_Pset_Matériaux - Face gauche: Ivoire clair; Face droite: Ivoire clair; Face latérale: Ivoire clair
Pset_WallCommon - Reference: default [627,07] (..\VERTICALES\Default\)
BaseQuantities - NominalWidth: 62.7069 cm
Name | __RECOGNIZE__, ID = IFC_Pset_Caractéristiques, ID | Numérotation | Longueur (cm) = NominalLength (cm) | IFC_Pset_Géométrie, Hauteur (cm) = IFC_Pset_Géométrie_P1 (POINT initial), Hauteur (cm) = IFC_Pset_Géométrie_P2 (POINT final), Hauteur (cm) = NominalHeight (cm) | delta (cm) = delta (P1) (cm) = delta (P2) (cm) | Longueur Pied (cm) = Longueur Tête (cm) | Hauteur Maximale (cm) = Hauteur Minimale (cm) | Surface en Plan (cm2) = Surface Pied (cm2) = Surface Tête (cm2) | Surface de la Paroi (cm2) | Volume (cm3) | GrossVolume (cm3) = NetVolume (cm3) | GrossFootprintArea (cm2) = NetFootprintArea (cm2) | GrossSideArea (cm2) = NetSideArea (cm2)
Enveloppe 44911 | 44911 | 0072 | 176.399 | 399.097 | -78.6853 | 176.4 | 399.1 | 11100 | 70400 | 4440000 | 4414598 | 11061.5 | 70400.5
Enveloppe 3039 | 3039 | 0017 | 44.7342 | 477.795 | 0.0128504 | 44.7 | 477.8 | 2800 | 21400 | 1350000 | 1340286 | 2805.15 | 21373.8

# IfcWallStandardCase: default 628.688354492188, Enveloppe 6013
In: Rez-de-chaussée
Type - Material: <aucun> 62.8688 cm
Description: Enveloppe; Group: ...de stratigraphies = default; ...de matériaux et couleurs = Ivoire clair; ...de matériaux et couleurs - 1 = Ivoire clair; ...de matériaux et couleurs - 2 = Ivoire clair
__RECOGNIZE__ - ID: 6013; TPLG: 366; TPLG_OD: 9000; GENERATE: 1
CTLG_EXTERNAL_LINK - 0, DocType: 2; 0, Tag: 0; 0, Crc: 1977773087; 1, DocType: 2; 1, Tag: 100; 1, Crc: 1977773087; 2, DocType: 2; 2, Tag: 200; 2, Crc: 1977773087; 3, DocType: 9; 3, Tag: 0; 3, Crc: 1541332338
IFC_PSET_PolygonOffset - polygonOffsetFactor: 2; polygonOffsetUnits: 2
IFC_Pset_Alignment - Alignment: 1
IFC_Pset_Strat_Detail_Align - ExternalFace: 0
IFC_Pset_Caractéristiques - ID: 6013; Numérotation: 0037; Numéro niveau: 03; Titre niveau: Rez-de-chaussée; Stratigraphie: default [628,69]; Épaisseur: 62.87 cm; Épaisseur VARIABLE: no
IFC_Pset_Caractéristiques_FRUIT - Fruit: no; Taille: 0 cm
IFC_Pset_Géométrie - Forme en Élévation: rectangle; Longueur: 65.8933 cm; Hauteur: 399.097 cm; Cote: 0.0128504 cm
IFC_Pset_Géométrie_P1 (POINT initial) - Hauteur: 399.097 cm; Cote: 0.0128504 cm; Angle XY: 0.41654 deg
IFC_Pset_Géométrie_P2 (POINT final) - Hauteur: 399.097 cm; Cote: 0.0128504 cm; Angle XY: 180.417 deg
IFC_Pset_Système de Référence Altimétrique_SUPÉRIEUR - NIVEAU: HAUT Rez-de-chaussée (Niveau 1 2343); delta: -78.6853 cm; delta (P1): -78.6853 cm; delta (P2): -78.6853 cm; sous Niveau: <aucun>
IFC_Pset_Système de Référence Altimétrique_INFÉRIEUR - NIVEAU: Rez-de-chaussée (Rez-de-chaussée 1047); delta: 0.0128504 cm; delta (P1): 0.0128504 cm; delta (P2): 0.0128504 cm; sous Niveau: <aucun>
IFC_Pset_Données Métré - Longueur Pied: 65.9 cm; Longueur Tête: 65.9 cm; Hauteur Maximale: 399.1 cm; Hauteur Minimale: 399.1 cm; Surface en Plan: 4200 cm2; Surface Pied: 4200 cm2; Surface Tête: 4200 cm2; Surface de la Paroi: 26300 cm2; Volume: 1660000 cm3
IFC_Pset_Matériaux - Face gauche: Ivoire clair; Face droite: Ivoire clair; Face latérale: Ivoire clair
Pset_WallCommon - Reference: default [628,69] (..\VERTICALES\Default\)
BaseQuantities - GrossVolume: 1653314 cm3; NetVolume: 1653314 cm3; NominalLength: 65.8933 cm; NominalWidth: 62.8688 cm; NominalHeight: 399.097 cm; GrossFootprintArea: 4142.63 cm2; NetFootprintArea: 4142.63 cm2; GrossSideArea: 26297.8 cm2; NetSideArea: 26297.8 cm2

# IfcWallStandardCase: default 629.010620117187, Enveloppe 161207
In: Rez-de-chaussée
Type - Material: <aucun> 62.9011 cm
Description: Enveloppe; Group: ...de stratigraphies = default; ...de matériaux et couleurs = Ivoire clair; ...de matériaux et couleurs - 1 = Ivoire clair; ...de matériaux et couleurs - 2 = Ivoire clair
__RECOGNIZE__ - ID: 161207; TPLG: 366; TPLG_OD: 9000; GENERATE: 1
CTLG_EXTERNAL_LINK - 0, DocType: 2; 0, Tag: 0; 0, Crc: 1977773087; 1, DocType: 2; 1, Tag: 100; 1, Crc: 1977773087; 2, DocType: 2; 2, Tag: 200; 2, Crc: 1977773087; 3, DocType: 9; 3, Tag: 0; 3, Crc: 1255674991
IFC_PSET_PolygonOffset - polygonOffsetFactor: 2; polygonOffsetUnits: 2
IFC_Pset_Alignment - Alignment: 0
IFC_Pset_Strat_Detail_Align - ExternalFace: 0
IFC_Pset_Caractéristiques - ID: 161207; Numérotation: 0384; Numéro niveau: 03; Titre niveau: Rez-de-chaussée; Stratigraphie: default [629,01]; Épaisseur: 62.9 cm; Épaisseur VARIABLE: no
IFC_Pset_Caractéristiques_FRUIT - Fruit: no; Taille: 0 cm
IFC_Pset_Géométrie - Forme en Élévation: rectangle; Longueur: 414.939 cm; Hauteur: 395.995 cm; Cote: 0.0128504 cm
IFC_Pset_Géométrie_P1 (POINT initial) - Hauteur: 395.995 cm; Cote: 0.0128504 cm; Angle XY: 90.174 deg
IFC_Pset_Géométrie_P2 (POINT final) - Hauteur: 395.995 cm; Cote: 0.0128504 cm; Angle XY: 270.174 deg
IFC_Pset_Système de Référence Altimétrique_SUPÉRIEUR - NIVEAU: HAUT Rez-de-chaussée (Niveau 1 2343); delta: -81.7871 cm; delta (P1): -81.7871 cm; delta (P2): -81.7871 cm; sous Niveau: <aucun>
IFC_Pset_Système de Référence Altimétrique_INFÉRIEUR - NIVEAU: Rez-de-chaussée (Rez-de-chaussée 1047); delta: 0.0128504 cm; delta (P1): 0.0128504 cm; delta (P2): 0.0128504 cm; sous Niveau: <aucun>
IFC_Pset_Données Métré - Longueur Pied: 414.9 cm; Longueur Tête: 414.9 cm; Hauteur Maximale: 396 cm; Hauteur Minimale: 396 cm; Surface en Plan: 26100 cm2; Surface Pied: 26100 cm2; Surface Tête: 26100 cm2; Surface de la Paroi: 164300 cm2; Volume: 10350000 cm3
IFC_Pset_Matériaux - Face gauche: Ivoire clair; Face droite: Ivoire clair; Face latérale: Ivoire clair
Pset_WallCommon - Reference: default [629,01] (..\VERTICALES\Default\)
BaseQuantities - GrossVolume: 10335519 cm3; NetVolume: 10335519 cm3; NominalLength: 414.939 cm; NominalWidth: 62.9011 cm; NominalHeight: 395.995 cm; GrossFootprintArea: 26100.1 cm2; NetFootprintArea: 26100.1 cm2; GrossSideArea: 164314 cm2; NetSideArea: 164314 cm2

# IfcWallStandardCase: default 63, Enveloppe 151230
In: Niveau 2
Type - Material: <aucun> 6.3 cm
Description: Enveloppe; Group: ...de stratigraphies = default; ...de matériaux et couleurs = Ivoire clair; ...de matériaux et couleurs - 1 = Ivoire clair; ...de matériaux et couleurs - 2 = Ivoire clair
__RECOGNIZE__ - ID: 151230; TPLG: 366; TPLG_OD: 9000; GENERATE: 1
CTLG_EXTERNAL_LINK - 0, DocType: 2; 0, Tag: 0; 0, Crc: 1977773087; 1, DocType: 2; 1, Tag: 100; 1, Crc: 1977773087; 2, DocType: 2; 2, Tag: 200; 2, Crc: 1977773087; 3, DocType: 9; 3, Tag: 0; 3, Crc: 1865716393
IFC_PSET_PolygonOffset - polygonOffsetFactor: 2; polygonOffsetUnits: 2
IFC_Pset_Alignment - Alignment: 0
IFC_Pset_Strat_Detail_Align - ExternalFace: 0
IFC_Pset_Caractéristiques - ID: 151230; Numérotation: 0349; Numéro niveau: 05; Titre niveau: Niveau 2; Stratigraphie: default [63,00]; Épaisseur: 6.3 cm; Épaisseur VARIABLE: yes
IFC_Pset_Caractéristiques_FRUIT - Fruit: no; Taille: 0 cm
IFC_Pset_Géométrie - Forme en Élévation: rectangle; Longueur: 148.902 cm; Hauteur: 208 cm; Cote: 1.42109e-12 cm
IFC_Pset_Géométrie_P1 (POINT initial) - Hauteur: 208 cm; Cote: 1.42109e-12 cm; Angle XY: 90.4179 deg
IFC_Pset_Géométrie_P2 (POINT final) - Hauteur: 208 cm; Cote: 1.42109e-12 cm; Angle XY: 270.418 deg
IFC_Pset_Système de Référence Altimétrique_SUPÉRIEUR - NIVEAU: HAUT Niveau 2 (Mezzanine 49003); delta: -27 cm; delta (P1): -27 cm; delta (P2): -27 cm; sous Niveau: <aucun>
IFC_Pset_Système de Référence Altimétrique_INFÉRIEUR - NIVEAU: Niveau 2 (Niveau 2 13545); delta: 1.42109e-12 cm; delta (P1): 1.42109e-12 cm; delta (P2): 1.42109e-12 cm; sous Niveau: <aucun>
IFC_Pset_Données Métré - Longueur Pied: 148.9 cm; Longueur Tête: 148.9 cm; Hauteur Maximale: 208 cm; Hauteur Minimale: 208 cm; Surface en Plan: 1000 cm2; Surface Pied: 1000 cm2; Surface Tête: 1000 cm2; Surface de la Paroi: 31000 cm2; Volume: 220000 cm3
IFC_Pset_Matériaux - Face gauche: Ivoire clair; Face droite: Ivoire clair; Face latérale: Ivoire clair
Pset_WallCommon - Reference: default [63,00] (..\VERTICALES\Default\)
BaseQuantities - GrossVolume: 217537 cm3; NetVolume: 217537 cm3; NominalLength: 148.902 cm; NominalWidth: 7.02372 cm; NominalHeight: 208 cm; GrossFootprintArea: 1045.85 cm2; NetFootprintArea: 1045.85 cm2; GrossSideArea: 30971.7 cm2; NetSideArea: 30971.7 cm2

# IfcWallStandardCase: default 630 (4)
Type - Material: <aucun> 63 cm
Description: Enveloppe; Group: ...de stratigraphies = default; ...de matériaux et couleurs = Ivoire clair; ...de matériaux et couleurs - 1 = Ivoire clair; ...de matériaux et couleurs - 2 = Ivoire clair
__RECOGNIZE__ - TPLG: 366; TPLG_OD: 9000; GENERATE: 1
CTLG_EXTERNAL_LINK - 0, DocType: 2; 0, Tag: 0; 0, Crc: 1977773087; 1, DocType: 2; 1, Tag: 100; 1, Crc: 1977773087; 2, DocType: 2; 2, Tag: 200; 2, Crc: 1977773087; 3, DocType: 9; 3, Tag: 0; 3, Crc: -1241460511
IFC_PSET_PolygonOffset - polygonOffsetFactor: 2; polygonOffsetUnits: 2
IFC_Pset_Caractéristiques - Stratigraphie: default [630,00]; Épaisseur: 63 cm
IFC_Pset_Caractéristiques_FRUIT - Fruit: no; Taille: 0 cm
IFC_Pset_Géométrie - Forme en Élévation: rectangle
IFC_Pset_Système de Référence Altimétrique_SUPÉRIEUR - delta: 0 cm; delta (P1): 0 cm; delta (P2): 0 cm; sous Niveau: <aucun>
IFC_Pset_Système de Référence Altimétrique_INFÉRIEUR - sous Niveau: <aucun>
IFC_Pset_Matériaux - Face gauche: Ivoire clair; Face droite: Ivoire clair; Face latérale: Ivoire clair
Pset_WallCommon - Reference: default [630,00] (..\VERTICALES\Default\)
Name | In | __RECOGNIZE__, ID = IFC_Pset_Caractéristiques, ID | Alignment | ExternalFace | Numérotation | Numéro niveau | Titre niveau | Épaisseur VARIABLE | Longueur (cm) = NominalLength (cm) | IFC_Pset_Géométrie, Hauteur (cm) = IFC_Pset_Géométrie_P1 (POINT initial), Hauteur (cm) = IFC_Pset_Géométrie_P2 (POINT final), Hauteur (cm) = NominalHeight (cm) | IFC_Pset_Géométrie, Cote (cm) = IFC_Pset_Géométrie_P1 (POINT initial), Cote (cm) = IFC_Pset_Géométrie_P2 (POINT final), Cote (cm) = delta (cm) = delta (P1) (cm) = delta (P2) (cm) | IFC_Pset_Géométrie_P1 (POINT initial), Angle XY (deg) | IFC_Pset_Géométrie_P2 (POINT final), Angle XY (deg) | IFC_Pset_Système de Référence Altimétrique_SUPÉRIEUR, NIVEAU | IFC_Pset_Système de Référence Altimétrique_INFÉRIEUR, NIVEAU | Longueur Pied (cm) = Longueur Tête (cm) | Hauteur Maximale (cm) = Hauteur Minimale (cm) | Surface en Plan (cm2) = Surface Pied (cm2) = Surface Tête (cm2) | Surface de la Paroi (cm2) | Volume (cm3) | GrossVolume (cm3) | NetVolume (cm3) | NominalWidth (cm) | GrossFootprintArea (cm2) = NetFootprintArea (cm2) | GrossSideArea (cm2) | NetSideArea (cm2)
Enveloppe 92672 | Niveau 1 | 92672 | 1 | 1 | 0189 | 04 | Niveau 1 | yes | 384.741 | 376.102 | 0.0128504 | 90.174 | 270.174 | HAUT Niveau 1 (Niveau 2 13545) | Niveau 1 (Niveau 1 2343) | 384.7 | 376.1 | 24500 | 144700 | 9260000 | 9198140 | 9198140 | 63.5661 | 24456.5 | 144702 | 144702
Enveloppe 93901 | Niveau 1 | 93901 | 0 | 0 | 0219 | 04 | Niveau 1 | no | 254.554 | 376.102 | 0.0128504 | 90.3835 | 270.384 | HAUT Niveau 1 (Niveau 2 13545) | Niveau 1 (Niveau 1 2343) | 254.6 | 376.1 | 16000 | 95800 | 6040000 | 6031503 | 6031503 | 63 | 16036.9 | 95738.1 | 95738.1
Enveloppe 118752 | Niveau 1 | 118752 | 0 | 0 | 0283 | 04 | Niveau 1 | yes | 319.927 | 376.102 | 0.0128504 | 0.100251 | 180.1 | HAUT Niveau 1 (Niveau 2 13545) | Niveau 1 (Niveau 1 2343) | 319.9 | 376.1 | 20400 | 120300 | 7700000 | 7682058 | 6638184 | 63.844 | 20425.5 | 120325 | 103852
Enveloppe 150377 | Niveau 2 | 150377 | 1 | 0 | 0328 | 05 | Niveau 2 | yes | 424.239 | 235 | 1.42109e-12 | 0.748882 | 180.749 | HAUT Niveau 2 (Mezzanine 49003) | Niveau 2 (Niveau 2 13545) | 424.2 | 235 | 27200 | 99700 | 6380000 | 6390175 | 6390175 | 64.0965 | 27192.2 | 99696.2 | 99696.2

# IfcWallStandardCase: default 65 (7)
Type - Material: <aucun> 6.5 cm
Description: Enveloppe
__RECOGNIZE__ - TPLG: 366; TPLG_OD: 9000; GENERATE: 1
CTLG_EXTERNAL_LINK - 0, DocType: 2; 0, Tag: 0; 1, DocType: 2; 1, Tag: 100; 2, DocType: 2; 2, Tag: 200; 3, DocType: 9; 3, Tag: 0; 3, Crc: 295283788
IFC_PSET_PolygonOffset - polygonOffsetFactor: 2; polygonOffsetUnits: 2
IFC_Pset_Caractéristiques - Stratigraphie: default [65,00]; Épaisseur: 6.5 cm
IFC_Pset_Caractéristiques_FRUIT - Fruit: no; Taille: 0 cm
IFC_Pset_Système de Référence Altimétrique_INFÉRIEUR - sous Niveau: <aucun>
Pset_WallCommon - Reference: default [65,00] (..\VERTICALES\Default\)
Name | In | __RECOGNIZE__, ID = IFC_Pset_Caractéristiques, ID | 0, Crc = 1, Crc = 2, Crc | Alignment | ExternalFace | Numérotation | Numéro niveau | Titre niveau | Épaisseur VARIABLE | Forme en Élévation | Longueur (cm) = NominalLength (cm) | IFC_Pset_Géométrie, Hauteur (cm) = IFC_Pset_Géométrie_P1 (POINT initial), Hauteur (cm) = IFC_Pset_Géométrie_P2 (POINT final), Hauteur (cm) = NominalHeight (cm) | IFC_Pset_Géométrie, Cote (cm) = IFC_Pset_Géométrie_P1 (POINT initial), Cote (cm) = IFC_Pset_Géométrie_P2 (POINT final), Cote (cm) = IFC_Pset_Système de Référence Altimétrique_INFÉRIEUR, delta (cm) = IFC_Pset_Système de Référence Altimétrique_INFÉRIEUR, delta (P1) (cm) = IFC_Pset_Système de Référence Altimétrique_INFÉRIEUR, delta (P2) (cm) | IFC_Pset_Géométrie_P1 (POINT initial), Angle XY (deg) | IFC_Pset_Géométrie_P2 (POINT final), Angle XY (deg) | IFC_Pset_Système de Référence Altimétrique_SUPÉRIEUR, NIVEAU | IFC_Pset_Système de Référence Altimétrique_SUPÉRIEUR, delta (cm) = IFC_Pset_Système de Référence Altimétrique_SUPÉRIEUR, delta (P1) (cm) = IFC_Pset_Système de Référence Altimétrique_SUPÉRIEUR, delta (P2) (cm) | sous Niveau | IFC_Pset_Système de Référence Altimétrique_INFÉRIEUR, NIVEAU | Longueur Pied (cm) = Longueur Tête (cm) | Hauteur Maximale (cm) = Hauteur Minimale (cm) | Surface en Plan (cm2) = Surface Pied (cm2) = Surface Tête (cm2) | Surface de la Paroi (cm2) | Volume (cm3) | Face gauche = Face droite = Face latérale | GrossVolume (cm3) | NetVolume (cm3) | NominalWidth (cm) | GrossFootprintArea (cm2) = NetFootprintArea (cm2) | GrossSideArea (cm2) | NetSideArea (cm2) | Group
Enveloppe 525107 | Rez-de-Jardin | 525107 | 1977773087 | 0 | 1 | 0841 | 02 | Rez-de-Jardin | no | rectangle | 147.578 | 285.4 | 106 | 135.684 | 315.684 | HAUT Rez-de-Jardin (Rez-de-chaussée 1047) | 100 | <aucun> | Rez-de-Jardin (Rez-de-Jardin 15545) | 147.6 | 285.4 | 1000 | 42100 | 290000 | Ivoire clair | 273773 | 5340.17 | 6.5 | 959.26 | 42118.9 | 821.564 | ...de stratigraphies = default; ...de matériaux et couleurs = Ivoire clair; ...de matériaux et couleurs - 1 = Ivoire clair; ...de matériaux et couleurs - 2 = Ivoire clair
Enveloppe 70012 | Rez-de-Jardin | 70012 | 1977773087 | 0 | 0 | 0137 | 02 | Rez-de-Jardin | no | rectangle | 100.753 | 291.413 | -1.94511e-11 | 0.219663 | 180.22 | HAUT Rez-de-Jardin (Rez-de-chaussée 1047) | 0.0128504 | <aucun> | Rez-de-Jardin (Rez-de-Jardin 15545) | 100.8 | 291.4 | 700 | 29400 | 210000 | Ivoire clair | 190845 | 190845 | 6.5 | 654.894 | 29360.7 | 29360.7 | ...de stratigraphies = default; ...de matériaux et couleurs = Ivoire clair; ...de matériaux et couleurs - 1 = Ivoire clair; ...de matériaux et couleurs - 2 = Ivoire clair
Enveloppe 132255 | Niveau 1 | 132255 | 1977773087 | 0 | 0 | 0301 | 04 | Niveau 1 | no | rectangle | 40.9161 | 376.102 | 0.0128504 | 179.777 | 359.777 | HAUT Niveau 1 (Niveau 2 13545) | 0 | <aucun> | Niveau 1 (Niveau 1 2343) | 40.9 | 376.1 | 300 | 15400 | 110000 | Ivoire clair | 100026 | 100026 | 6.5 | 265.955 | 15388.6 | 15388.6 | ...de stratigraphies = default; ...de matériaux et couleurs = Ivoire clair; ...de matériaux et couleurs - 1 = Ivoire clair; ...de matériaux et couleurs - 2 = Ivoire clair
Enveloppe 132594 | Niveau 1 | 132594 | 1977773087 | 0 | 0 | 0305 | 04 | Niveau 1 | no | rectangle | 143.357 | 376.102 | 0.0128504 | 179.777 | 359.777 | HAUT Niveau 1 (Niveau 2 13545) | 0 | <aucun> | Niveau 1 (Niveau 1 2343) | 143.4 | 376.1 | 1000 | 53900 | 380000 | Ivoire clair | 350460 | 215261 | 6.5 | 931.821 | 53916.9 | 33117 | ...de stratigraphies = default; ...de matériaux et couleurs = Ivoire clair; ...de matériaux et couleurs - 1 = Ivoire clair; ...de matériaux et couleurs - 2 = Ivoire clair
Enveloppe 150684 | Niveau 2 | 150684 | 1977773087 | 1 | 0 | 0336 | 05 | Niveau 2 | yes | rectangle | 137.831 | 235 | 1.42109e-12 | 1.05781 | 181.058 | HAUT Niveau 2 (Mezzanine 49003) | 0 | <aucun> | Niveau 2 (Niveau 2 13545) | 137.8 | 235 | 1000 | 32400 | 230000 | Ivoire clair | 233244 | 92343.7 | 7.20104 | 992.529 | 32390.4 | 12793.5 | ...de stratigraphies = default; ...de matériaux et couleurs = Ivoire clair; ...de matériaux et couleurs - 1 = Ivoire clair; ...de matériaux et couleurs - 2 = Ivoire clair
Enveloppe 170648 | Niveau 2 | 170648 | 1977773087 | 1 | 0 | 0422 | 05 | Niveau 2 | no | rectangle | 63.0751 | 225 | 1.42109e-12 | 90.7503 | 270.75 | HAUT Niveau 2 (Mezzanine 49003) | -10 | <aucun> | Niveau 2 (Niveau 2 13545) | 63.1 | 225 | 400 | 14200 | 100000 | Ivoire clair | 92247.4 | 92247.4 | 6.5 | 409.988 | 14191.9 | 14191.9 | ...de stratigraphies = default; ...de matériaux et couleurs = Ivoire clair; ...de matériaux et couleurs - 1 = Ivoire clair; ...de matériaux et couleurs - 2 = Ivoire clair
Enveloppe 197791 | Mezzanine | 197791 | -1156274542 | 0 | 1 | 0496 | 06 | Mezzanine | no | trapèze | 20.2556 | 227.912 | 3.73035e-12 | 0.635226 | 180.635 | Couverture (Couverture 2134) | 0 | Toit793923 | Mezzanine (Mezzanine 49003) | 20.3 | 227.9 | 100 | 4600 | 30000 | Chêne | 30007.1 | 30007.1 | 6.5 | 131.661 | 4616.48 | 4616.48 | ...de matériaux et couleurs = Chêne; ...de stratigraphies = default; ...de matériaux et couleurs - 1 = Chêne; ...de matériaux et couleurs - 2 = Chêne

# IfcWallStandardCase: default 66.175895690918 (3)
In: Rez-de-chaussée
Type - Material: <aucun> 6.61759 cm
Description: Enveloppe; Group: ...de stratigraphies = default; ...de matériaux et couleurs = Ivoire clair; ...de matériaux et couleurs - 1 = Ivoire clair; ...de matériaux et couleurs - 2 = Ivoire clair
__RECOGNIZE__ - TPLG: 366; TPLG_OD: 9000; GENERATE: 1
CTLG_EXTERNAL_LINK - 0, DocType: 2; 0, Tag: 0; 0, Crc: 1977773087; 1, DocType: 2; 1, Tag: 100; 1, Crc: 1977773087; 2, DocType: 2; 2, Tag: 200; 2, Crc: 1977773087; 3, DocType: 9; 3, Tag: 0; 3, Crc: 1158444728
IFC_PSET_PolygonOffset - polygonOffsetFactor: 2; polygonOffsetUnits: 2
IFC_Pset_Alignment - Alignment: 0
IFC_Pset_Strat_Detail_Align - ExternalFace: 0
IFC_Pset_Caractéristiques - Numéro niveau: 03; Titre niveau: Rez-de-chaussée; Stratigraphie: default [66,18]; Épaisseur: 6.62 cm; Épaisseur VARIABLE: no
IFC_Pset_Caractéristiques_FRUIT - Fruit: no; Taille: 0 cm
IFC_Pset_Géométrie - Forme en Élévation: rectangle; Hauteur: 247.862 cm; Cote: 0.0128504 cm
IFC_Pset_Géométrie_P1 (POINT initial) - Hauteur: 247.862 cm; Cote: 0.0128504 cm
IFC_Pset_Géométrie_P2 (POINT final) - Hauteur: 247.862 cm; Cote: 0.0128504 cm
IFC_Pset_Système de Référence Altimétrique_SUPÉRIEUR - NIVEAU: HAUT Rez-de-chaussée (Niveau 1 2343); delta: -229.921 cm; delta (P1): -229.921 cm; delta (P2): -229.921 cm; sous Niveau: <aucun>
IFC_Pset_Système de Référence Altimétrique_INFÉRIEUR - NIVEAU: Rez-de-chaussée (Rez-de-chaussée 1047); delta: 0.0128504 cm; delta (P1): 0.0128504 cm; delta (P2): 0.0128504 cm; sous Niveau: <aucun>
IFC_Pset_Données Métré - Hauteur Maximale: 247.9 cm; Hauteur Minimale: 247.9 cm
IFC_Pset_Matériaux - Face gauche: Ivoire clair; Face droite: Ivoire clair; Face latérale: Ivoire clair
Pset_WallCommon - Reference: default [66,18] (..\VERTICALES\Default\)
BaseQuantities - NominalWidth: 6.61759 cm; NominalHeight: 247.862 cm
Name | __RECOGNIZE__, ID = IFC_Pset_Caractéristiques, ID | Numérotation | Longueur (cm) = NominalLength (cm) | IFC_Pset_Géométrie_P1 (POINT initial), Angle XY (deg) | IFC_Pset_Géométrie_P2 (POINT final), Angle XY (deg) | Longueur Pied (cm) = Longueur Tête (cm) | Surface en Plan (cm2) = Surface Pied (cm2) = Surface Tête (cm2) | Surface de la Paroi (cm2) | Volume (cm3) | GrossVolume (cm3) = NetVolume (cm3) | GrossFootprintArea (cm2) = NetFootprintArea (cm2) | GrossSideArea (cm2) = NetSideArea (cm2)
Enveloppe 3381 | 3381 | 0028 | 112.437 | 0.130346 | 180.13 | 112.4 | 800 | 27900 | 200000 | 184425 | 744.065 | 27868.9
Enveloppe 3314 | 3314 | 0026 | 111.407 | 0.130346 | 180.13 | 111.4 | 800 | 27600 | 190000 | 182736 | 737.248 | 27613.6
Enveloppe 5701 | 5701 | 0035 | 197.472 | 90.1634 | 270.163 | 197.5 | 1400 | 49000 | 340000 | 323903 | 1306.79 | 48945.7

# IfcWallStandardCase: default 66.8023300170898, Enveloppe 150635
In: Niveau 2
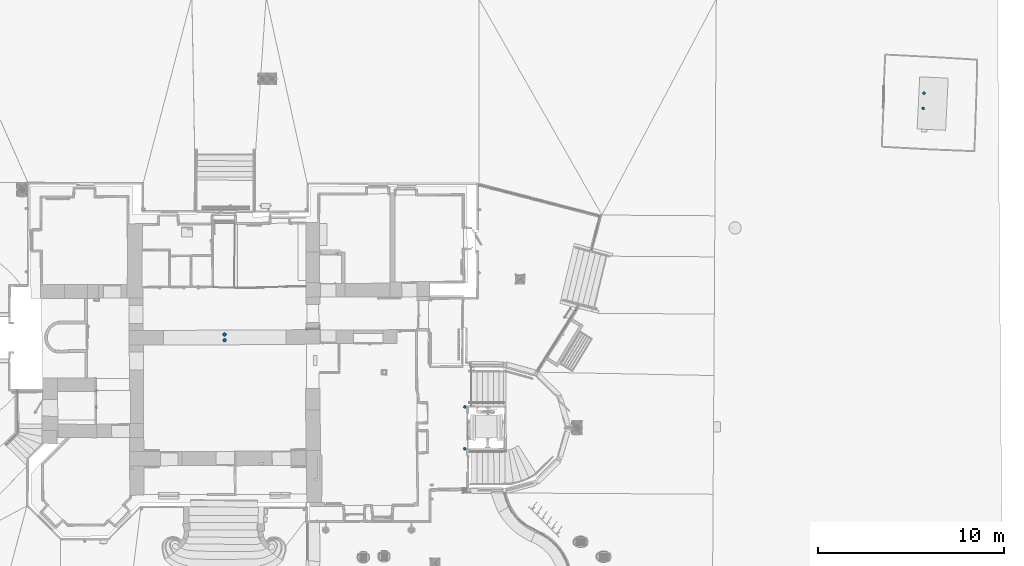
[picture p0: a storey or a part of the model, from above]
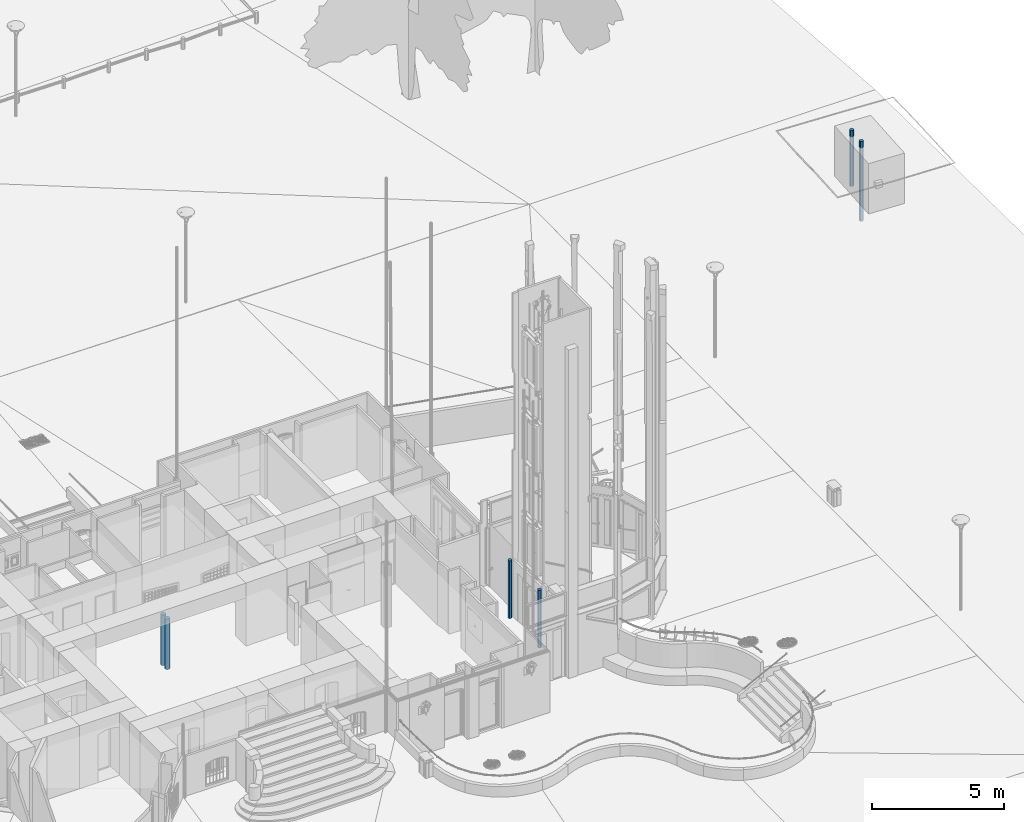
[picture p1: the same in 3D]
Properties of the parts of a building model (IFC2X3), part 27 of 37

# IfcWallStandardCase: default 66.8023300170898, Enveloppe 150635
Type - Material: <aucun> 6.68023 cm
Description: Enveloppe; Group: ...de stratigraphies = default; ...de matériaux et couleurs = Ivoire clair; ...de matériaux et couleurs - 1 = Ivoire clair; ...de matériaux et couleurs - 2 = Ivoire clair
__RECOGNIZE__ - ID: 150635; TPLG: 366; TPLG_OD: 9000; GENERATE: 1
CTLG_EXTERNAL_LINK - 0, DocType: 2; 0, Tag: 0; 0, Crc: 1977773087; 1, DocType: 2; 1, Tag: 100; 1, Crc: 1977773087; 2, DocType: 2; 2, Tag: 200; 2, Crc: 1977773087; 3, DocType: 9; 3, Tag: 0; 3, Crc: 387881132
IFC_PSET_PolygonOffset - polygonOffsetFactor: 2; polygonOffsetUnits: 2
IFC_Pset_Alignment - Alignment: 0
IFC_Pset_Strat_Detail_Align - ExternalFace: 0
IFC_Pset_Caractéristiques - ID: 150635; Numérotation: 0332; Numéro niveau: 05; Titre niveau: Niveau 2; Stratigraphie: default [66,80]; Épaisseur: 6.68 cm; Épaisseur VARIABLE: no
IFC_Pset_Caractéristiques_FRUIT - Fruit: no; Taille: 0 cm
IFC_Pset_Géométrie - Forme en Élévation: rectangle; Longueur: 148.349 cm; Hauteur: 215 cm; Cote: 1.42109e-12 cm
IFC_Pset_Géométrie_P1 (POINT initial) - Hauteur: 215 cm; Cote: 1.42109e-12 cm; Angle XY: 0.511011 deg
IFC_Pset_Géométrie_P2 (POINT final) - Hauteur: 215 cm; Cote: 1.42109e-12 cm; Angle XY: 180.511 deg
IFC_Pset_Système de Référence Altimétrique_SUPÉRIEUR - NIVEAU: HAUT Niveau 2 (Mezzanine 49003); delta: -20 cm; delta (P1): -20 cm; delta (P2): -20 cm; sous Niveau: <aucun>
IFC_Pset_Système de Référence Altimétrique_INFÉRIEUR - NIVEAU: Niveau 2 (Niveau 2 13545); delta: 1.42109e-12 cm; delta (P1): 1.42109e-12 cm; delta (P2): 1.42109e-12 cm; sous Niveau: <aucun>
IFC_Pset_Données Métré - Longueur Pied: 148.3 cm; Longueur Tête: 148.3 cm; Hauteur Maximale: 215 cm; Hauteur Minimale: 215 cm; Surface en Plan: 1000 cm2; Surface Pied: 1000 cm2; Surface Tête: 1000 cm2; Surface de la Paroi: 31900 cm2; Volume: 220000 cm3
IFC_Pset_Matériaux - Face gauche: Ivoire clair; Face droite: Ivoire clair; Face latérale: Ivoire clair
Pset_WallCommon - Reference: default [66,80] (..\VERTICALES\Default\)
BaseQuantities - GrossVolume: 213067 cm3; NetVolume: 213067 cm3; NominalLength: 148.349 cm; NominalWidth: 6.68023 cm; NominalHeight: 215 cm; GrossFootprintArea: 991.007 cm2; NetFootprintArea: 991.007 cm2; GrossSideArea: 31895.1 cm2; NetSideArea: 31895.1 cm2

# IfcWallStandardCase: default 660, Enveloppe 150855
In: Niveau 2
Type - Material: <aucun> 66 cm
Description: Enveloppe; Group: ...de stratigraphies = default; ...de matériaux et couleurs = Ivoire clair; ...de matériaux et couleurs - 1 = Ivoire clair; ...de matériaux et couleurs - 2 = Ivoire clair
__RECOGNIZE__ - ID: 150855; TPLG: 366; TPLG_OD: 9000; GENERATE: 1
CTLG_EXTERNAL_LINK - 0, DocType: 2; 0, Tag: 0; 0, Crc: 1977773087; 1, DocType: 2; 1, Tag: 100; 1, Crc: 1977773087; 2, DocType: 2; 2, Tag: 200; 2, Crc: 1977773087; 3, DocType: 9; 3, Tag: 0; 3, Crc: -249973915
IFC_PSET_PolygonOffset - polygonOffsetFactor: 2; polygonOffsetUnits: 2
IFC_Pset_Alignment - Alignment: 1
IFC_Pset_Strat_Detail_Align - ExternalFace: 0
IFC_Pset_Caractéristiques - ID: 150855; Numérotation: 0343; Numéro niveau: 05; Titre niveau: Niveau 2; Stratigraphie: default [660,00]; Épaisseur: 66 cm; Épaisseur VARIABLE: no
IFC_Pset_Caractéristiques_FRUIT - Fruit: no; Taille: 0 cm
IFC_Pset_Géométrie - Forme en Élévation: rectangle; Longueur: 38.7677 cm; Hauteur: 218.5 cm; Cote: 1.42109e-12 cm
IFC_Pset_Géométrie_P1 (POINT initial) - Hauteur: 218.5 cm; Cote: 1.42109e-12 cm; Angle XY: 90.174 deg
IFC_Pset_Géométrie_P2 (POINT final) - Hauteur: 218.5 cm; Cote: 1.42109e-12 cm; Angle XY: 270.174 deg
IFC_Pset_Système de Référence Altimétrique_SUPÉRIEUR - NIVEAU: HAUT Niveau 2 (Mezzanine 49003); delta: -16.5 cm; delta (P1): -16.5 cm; delta (P2): -16.5 cm; sous Niveau: <aucun>
IFC_Pset_Système de Référence Altimétrique_INFÉRIEUR - NIVEAU: Niveau 2 (Niveau 2 13545); delta: 1.42109e-12 cm; delta (P1): 1.42109e-12 cm; delta (P2): 1.42109e-12 cm; sous Niveau: <aucun>
IFC_Pset_Données Métré - Longueur Pied: 38.8 cm; Longueur Tête: 38.8 cm; Hauteur Maximale: 218.5 cm; Hauteur Minimale: 218.5 cm; Surface en Plan: 2600 cm2; Surface Pied: 2600 cm2; Surface Tête: 2600 cm2; Surface de la Paroi: 8500 cm2; Volume: 560000 cm3
IFC_Pset_Matériaux - Face gauche: Ivoire clair; Face droite: Ivoire clair; Face latérale: Ivoire clair
Pset_WallCommon - Reference: default [660,00] (..\VERTICALES\Default\)
BaseQuantities - GrossVolume: 559069 cm3; NetVolume: 559069 cm3; NominalLength: 38.7677 cm; NominalWidth: 66 cm; NominalHeight: 218.5 cm; GrossFootprintArea: 2558.67 cm2; NetFootprintArea: 2558.67 cm2; GrossSideArea: 8470.74 cm2; NetSideArea: 8470.74 cm2

# IfcWallStandardCase: default 665, Enveloppe 150856
In: Niveau 2
Type - Material: <aucun> 66.5 cm
Description: Enveloppe; Group: ...de stratigraphies = default; ...de matériaux et couleurs = Ivoire clair; ...de matériaux et couleurs - 1 = Ivoire clair; ...de matériaux et couleurs - 2 = Ivoire clair
__RECOGNIZE__ - ID: 150856; TPLG: 366; TPLG_OD: 9000; GENERATE: 1
CTLG_EXTERNAL_LINK - 0, DocType: 2; 0, Tag: 0; 0, Crc: 1977773087; 1, DocType: 2; 1, Tag: 100; 1, Crc: 1977773087; 2, DocType: 2; 2, Tag: 200; 2, Crc: 1977773087; 3, DocType: 9; 3, Tag: 0; 3, Crc: 2125319693
IFC_PSET_PolygonOffset - polygonOffsetFactor: 2; polygonOffsetUnits: 2
IFC_Pset_Alignment - Alignment: 1
IFC_Pset_Strat_Detail_Align - ExternalFace: 0
IFC_Pset_Caractéristiques - ID: 150856; Numérotation: 0344; Numéro niveau: 05; Titre niveau: Niveau 2; Stratigraphie: default [665,00]; Épaisseur: 66.5 cm; Épaisseur VARIABLE: no
IFC_Pset_Caractéristiques_FRUIT - Fruit: no; Taille: 0 cm
IFC_Pset_Géométrie - Forme en Élévation: rectangle; Longueur: 61.4168 cm; Hauteur: 218.5 cm; Cote: 1.42109e-12 cm
IFC_Pset_Géométrie_P1 (POINT initial) - Hauteur: 218.5 cm; Cote: 1.42109e-12 cm; Angle XY: 91.055 deg
IFC_Pset_Géométrie_P2 (POINT final) - Hauteur: 218.5 cm; Cote: 1.42109e-12 cm; Angle XY: 271.055 deg
IFC_Pset_Système de Référence Altimétrique_SUPÉRIEUR - NIVEAU: HAUT Niveau 2 (Mezzanine 49003); delta: -16.5 cm; delta (P1): -16.5 cm; delta (P2): -16.5 cm; sous Niveau: <aucun>
IFC_Pset_Système de Référence Altimétrique_INFÉRIEUR - NIVEAU: Niveau 2 (Niveau 2 13545); delta: 1.42109e-12 cm; delta (P1): 1.42109e-12 cm; delta (P2): 1.42109e-12 cm; sous Niveau: <aucun>
IFC_Pset_Données Métré - Longueur Pied: 61.4 cm; Longueur Tête: 61.4 cm; Hauteur Maximale: 218.5 cm; Hauteur Minimale: 218.5 cm; Surface en Plan: 4100 cm2; Surface Pied: 4100 cm2; Surface Tête: 4100 cm2; Surface de la Paroi: 13400 cm2; Volume: 900000 cm3
IFC_Pset_Matériaux - Face gauche: Ivoire clair; Face droite: Ivoire clair; Face latérale: Ivoire clair
Pset_WallCommon - Reference: default [665,00] (..\VERTICALES\Default\)
BaseQuantities - GrossVolume: 892402 cm3; NetVolume: 892402 cm3; NominalLength: 61.4168 cm; NominalWidth: 66.5 cm; NominalHeight: 218.5 cm; GrossFootprintArea: 4084.22 cm2; NetFootprintArea: 4084.22 cm2; GrossSideArea: 13419.6 cm2; NetSideArea: 13419.6 cm2

# IfcWallStandardCase: default 67, Enveloppe 95138
In: Niveau 1
Type - Material: <aucun> 6.7 cm
Description: Enveloppe; Group: ...de stratigraphies = default; ...de matériaux et couleurs = Ivoire clair; ...de matériaux et couleurs - 1 = Ivoire clair; ...de matériaux et couleurs - 2 = Ivoire clair
__RECOGNIZE__ - ID: 95138; TPLG: 366; TPLG_OD: 9000; GENERATE: 1
CTLG_EXTERNAL_LINK - 0, DocType: 2; 0, Tag: 0; 0, Crc: 1977773087; 1, DocType: 2; 1, Tag: 100; 1, Crc: 1977773087; 2, DocType: 2; 2, Tag: 200; 2, Crc: 1977773087; 3, DocType: 9; 3, Tag: 0; 3, Crc: 1815272692
IFC_PSET_PolygonOffset - polygonOffsetFactor: 2; polygonOffsetUnits: 2
IFC_Pset_Alignment - Alignment: 0
IFC_Pset_Strat_Detail_Align - ExternalFace: 0
IFC_Pset_Caractéristiques - ID: 95138; Numérotation: 0244; Numéro niveau: 04; Titre niveau: Niveau 1; Stratigraphie: default [67,00]; Épaisseur: 6.7 cm; Épaisseur VARIABLE: no
IFC_Pset_Caractéristiques_FRUIT - Fruit: no; Taille: 0 cm
IFC_Pset_Géométrie - Forme en Élévation: rectangle; Longueur: 149.312 cm; Hauteur: 238.102 cm; Cote: 0.0128504 cm
IFC_Pset_Géométrie_P1 (POINT initial) - Hauteur: 238.102 cm; Cote: 0.0128504 cm; Angle XY: 90.3851 deg
IFC_Pset_Géométrie_P2 (POINT final) - Hauteur: 238.102 cm; Cote: 0.0128504 cm; Angle XY: 270.385 deg
IFC_Pset_Système de Référence Altimétrique_SUPÉRIEUR - NIVEAU: HAUT Niveau 1 (Niveau 2 13545); delta: -138 cm; delta (P1): -138 cm; delta (P2): -138 cm; sous Niveau: <aucun>
IFC_Pset_Système de Référence Altimétrique_INFÉRIEUR - NIVEAU: Niveau 1 (Niveau 1 2343); delta: 0.0128504 cm; delta (P1): 0.0128504 cm; delta (P2): 0.0128504 cm; sous Niveau: <aucun>
IFC_Pset_Données Métré - Longueur Pied: 149.3 cm; Longueur Tête: 149.3 cm; Hauteur Maximale: 238.1 cm; Hauteur Minimale: 238.1 cm; Surface en Plan: 1000 cm2; Surface Pied: 1000 cm2; Surface Tête: 1000 cm2; Surface de la Paroi: 35500 cm2; Volume: 250000 cm3
IFC_Pset_Matériaux - Face gauche: Ivoire clair; Face droite: Ivoire clair; Face latérale: Ivoire clair
Pset_WallCommon - Reference: default [67,00] (..\VERTICALES\Default\)
BaseQuantities - GrossVolume: 238195 cm3; NetVolume: 238195 cm3; NominalLength: 149.312 cm; NominalWidth: 6.7 cm; NominalHeight: 238.102 cm; GrossFootprintArea: 1000.39 cm2; NetFootprintArea: 1000.39 cm2; GrossSideArea: 35551.5 cm2; NetSideArea: 35551.5 cm2

# IfcWallStandardCase: default 68 (2)
In: Niveau 1
Type - Material: <aucun> 6.8 cm
Description: Enveloppe; Group: ...de stratigraphies = default; ...de matériaux et couleurs = Ivoire clair; ...de matériaux et couleurs - 1 = Ivoire clair; ...de matériaux et couleurs - 2 = Ivoire clair
__RECOGNIZE__ - TPLG: 366; TPLG_OD: 9000; GENERATE: 1
CTLG_EXTERNAL_LINK - 0, DocType: 2; 0, Tag: 0; 0, Crc: 1977773087; 1, DocType: 2; 1, Tag: 100; 1, Crc: 1977773087; 2, DocType: 2; 2, Tag: 200; 2, Crc: 1977773087; 3, DocType: 9; 3, Tag: 0; 3, Crc: 2119759306
IFC_PSET_PolygonOffset - polygonOffsetFactor: 2; polygonOffsetUnits: 2
IFC_Pset_Alignment - Alignment: 1
IFC_Pset_Strat_Detail_Align - ExternalFace: 0
IFC_Pset_Caractéristiques - Numéro niveau: 04; Titre niveau: Niveau 1; Stratigraphie: default [68,00]; Épaisseur: 6.8 cm; Épaisseur VARIABLE: no
IFC_Pset_Caractéristiques_FRUIT - Fruit: no; Taille: 0 cm
IFC_Pset_Géométrie - Forme en Élévation: rectangle; Hauteur: 238.102 cm; Cote: 0.0128504 cm
IFC_Pset_Géométrie_P1 (POINT initial) - Hauteur: 238.102 cm; Cote: 0.0128504 cm
IFC_Pset_Géométrie_P2 (POINT final) - Hauteur: 238.102 cm; Cote: 0.0128504 cm
IFC_Pset_Système de Référence Altimétrique_SUPÉRIEUR - NIVEAU: HAUT Niveau 1 (Niveau 2 13545); delta: -138 cm; delta (P1): -138 cm; delta (P2): -138 cm; sous Niveau: <aucun>
IFC_Pset_Système de Référence Altimétrique_INFÉRIEUR - NIVEAU: Niveau 1 (Niveau 1 2343); delta: 0.0128504 cm; delta (P1): 0.0128504 cm; delta (P2): 0.0128504 cm; sous Niveau: <aucun>
IFC_Pset_Données Métré - Hauteur Maximale: 238.1 cm; Hauteur Minimale: 238.1 cm; Surface en Plan: 1000 cm2; Surface Pied: 1000 cm2; Surface Tête: 1000 cm2; Surface de la Paroi: 34700 cm2; Volume: 240000 cm3
IFC_Pset_Matériaux - Face gauche: Ivoire clair; Face droite: Ivoire clair; Face latérale: Ivoire clair
Pset_WallCommon - Reference: default [68,00] (..\VERTICALES\Default\)
BaseQuantities - NominalWidth: 6.8 cm; NominalHeight: 238.102 cm
Name | __RECOGNIZE__, ID = IFC_Pset_Caractéristiques, ID | Numérotation | Longueur (cm) = NominalLength (cm) | IFC_Pset_Géométrie_P1 (POINT initial), Angle XY (deg) | IFC_Pset_Géométrie_P2 (POINT final), Angle XY (deg) | Longueur Pied (cm) = Longueur Tête (cm) | GrossVolume (cm3) = NetVolume (cm3) | GrossFootprintArea (cm2) = NetFootprintArea (cm2) | GrossSideArea (cm2) = NetSideArea (cm2)
Enveloppe 93081 | 93081 | 0199 | 145.876 | 89.8395 | 269.839 | 145.9 | 236186 | 991.954 | 34733.3
Enveloppe 93092 | 93092 | 0200 | 145.755 | 90.1852 | 270.185 | 145.8 | 235991 | 991.134 | 34704.6

# IfcWallStandardCase: default 680, Enveloppe 67417
In: Rez-de-Jardin
Type - Material: <aucun> 68 cm
Description: Enveloppe; Group: ...de stratigraphies = default; ...de matériaux et couleurs = Ivoire clair; ...de matériaux et couleurs - 1 = Ivoire clair; ...de matériaux et couleurs - 2 = Ivoire clair
__RECOGNIZE__ - ID: 67417; TPLG: 366; TPLG_OD: 9000; GENERATE: 1
CTLG_EXTERNAL_LINK - 0, DocType: 2; 0, Tag: 0; 0, Crc: 1977773087; 1, DocType: 2; 1, Tag: 100; 1, Crc: 1977773087; 2, DocType: 2; 2, Tag: 200; 2, Crc: 1977773087; 3, DocType: 9; 3, Tag: 0; 3, Crc: 1349014997
IFC_PSET_PolygonOffset - polygonOffsetFactor: 2; polygonOffsetUnits: 2
IFC_Pset_Alignment - Alignment: 0
IFC_Pset_Strat_Detail_Align - ExternalFace: 1
IFC_Pset_Caractéristiques - ID: 67417; Numérotation: 0126; Numéro niveau: 02; Titre niveau: Rez-de-Jardin; Stratigraphie: default [680,00]; Épaisseur: 68 cm; Épaisseur VARIABLE: no
IFC_Pset_Caractéristiques_FRUIT - Fruit: no; Taille: 0 cm
IFC_Pset_Géométrie - Forme en Élévation: rectangle; Longueur: 183.054 cm; Hauteur: 291.413 cm; Cote: -1.94511e-11 cm
IFC_Pset_Géométrie_P1 (POINT initial) - Hauteur: 291.413 cm; Cote: -1.94511e-11 cm; Angle XY: 89.6478 deg
IFC_Pset_Géométrie_P2 (POINT final) - Hauteur: 291.413 cm; Cote: -1.94511e-11 cm; Angle XY: 269.648 deg
IFC_Pset_Système de Référence Altimétrique_SUPÉRIEUR - NIVEAU: HAUT Rez-de-Jardin (Rez-de-chaussée 1047); delta: 0.0128504 cm; delta (P1): 0.0128504 cm; delta (P2): 0.0128504 cm; sous Niveau: <aucun>
IFC_Pset_Système de Référence Altimétrique_INFÉRIEUR - NIVEAU: Rez-de-Jardin (Rez-de-Jardin 15545); delta: -1.94511e-11 cm; delta (P1): -1.94511e-11 cm; delta (P2): -1.94511e-11 cm; sous Niveau: <aucun>
IFC_Pset_Données Métré - Longueur Pied: 183.1 cm; Longueur Tête: 183.1 cm; Hauteur Maximale: 291.4 cm; Hauteur Minimale: 291.4 cm; Surface en Plan: 12500 cm2; Surface Pied: 12500 cm2; Surface Tête: 12500 cm2; Surface de la Paroi: 53400 cm2; Volume: 3630000 cm3
IFC_Pset_Matériaux - Face gauche: Ivoire clair; Face droite: Ivoire clair; Face latérale: Ivoire clair
Pset_WallCommon - Reference: default [680,00] (..\VERTICALES\Default\)
BaseQuantities - GrossVolume: 3627425 cm3; NetVolume: 1559801 cm3; NominalLength: 183.054 cm; NominalWidth: 68 cm; NominalHeight: 291.413 cm; GrossFootprintArea: 12447.7 cm2; NetFootprintArea: 12447.7 cm2; GrossSideArea: 53344.5 cm2; NetSideArea: 22938.2 cm2

# IfcWallStandardCase: default 69.3186492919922, Enveloppe 150609
In: Niveau 2
Type - Material: <aucun> 6.93186 cm
Description: Enveloppe; Group: ...de stratigraphies = default; ...de matériaux et couleurs = Ivoire clair; ...de matériaux et couleurs - 1 = Ivoire clair; ...de matériaux et couleurs - 2 = Ivoire clair
__RECOGNIZE__ - ID: 150609; TPLG: 366; TPLG_OD: 9000; GENERATE: 1
CTLG_EXTERNAL_LINK - 0, DocType: 2; 0, Tag: 0; 0, Crc: 1977773087; 1, DocType: 2; 1, Tag: 100; 1, Crc: 1977773087; 2, DocType: 2; 2, Tag: 200; 2, Crc: 1977773087; 3, DocType: 9; 3, Tag: 0; 3, Crc: 722976859
IFC_PSET_PolygonOffset - polygonOffsetFactor: 2; polygonOffsetUnits: 2
IFC_Pset_Alignment - Alignment: 0
IFC_Pset_Strat_Detail_Align - ExternalFace: 0
IFC_Pset_Caractéristiques - ID: 150609; Numérotation: 0331; Numéro niveau: 05; Titre niveau: Niveau 2; Stratigraphie: default [69,32]; Épaisseur: 6.93 cm; Épaisseur VARIABLE: no
IFC_Pset_Caractéristiques_FRUIT - Fruit: no; Taille: 0 cm
IFC_Pset_Géométrie - Forme en Élévation: rectangle; Longueur: 148.388 cm; Hauteur: 209 cm; Cote: 1.42109e-12 cm
IFC_Pset_Géométrie_P1 (POINT initial) - Hauteur: 209 cm; Cote: 1.42109e-12 cm; Angle XY: 90.3575 deg
IFC_Pset_Géométrie_P2 (POINT final) - Hauteur: 209 cm; Cote: 1.42109e-12 cm; Angle XY: 270.357 deg
IFC_Pset_Système de Référence Altimétrique_SUPÉRIEUR - NIVEAU: HAUT Niveau 2 (Mezzanine 49003); delta: -26 cm; delta (P1): -26 cm; delta (P2): -26 cm; sous Niveau: <aucun>
IFC_Pset_Système de Référence Altimétrique_INFÉRIEUR - NIVEAU: Niveau 2 (Niveau 2 13545); delta: 1.42109e-12 cm; delta (P1): 1.42109e-12 cm; delta (P2): 1.42109e-12 cm; sous Niveau: <aucun>
IFC_Pset_Données Métré - Longueur Pied: 148.4 cm; Longueur Tête: 148.4 cm; Hauteur Maximale: 209 cm; Hauteur Minimale: 209 cm; Surface en Plan: 1000 cm2; Surface Pied: 1000 cm2; Surface Tête: 1000 cm2; Surface de la Paroi: 31000 cm2; Volume: 220000 cm3
IFC_Pset_Matériaux - Face gauche: Ivoire clair; Face droite: Ivoire clair; Face latérale: Ivoire clair
Pset_WallCommon - Reference: default [69,32] (..\VERTICALES\Default\)
BaseQuantities - GrossVolume: 214978 cm3; NetVolume: 214978 cm3; NominalLength: 148.388 cm; NominalWidth: 6.93187 cm; NominalHeight: 209 cm; GrossFootprintArea: 1028.6 cm2; NetFootprintArea: 1028.6 cm2; GrossSideArea: 31013.1 cm2; NetSideArea: 31013.1 cm2

# IfcWallStandardCase: default 70 (33)
Type - Material: <aucun> 7 cm
__RECOGNIZE__ - GENERATE: 1
CTLG_EXTERNAL_LINK - 0, DocType: 2; 0, Tag: 0; 1, DocType: 2; 1, Tag: 100; 2, DocType: 2; 2, Tag: 200; 3, DocType: 9; 3, Tag: 0; 3, Crc: 1476981794
IFC_PSET_PolygonOffset - polygonOffsetFactor: 2; polygonOffsetUnits: 2
IFC_Pset_Caractéristiques - Stratigraphie: default [70,00]; Épaisseur: 7 cm
IFC_Pset_Caractéristiques_FRUIT - Fruit: no; Taille: 0 cm
IFC_Pset_Géométrie - Forme en Élévation: rectangle
IFC_Pset_Système de Référence Altimétrique_SUPÉRIEUR - sous Niveau: <aucun>
IFC_Pset_Système de Référence Altimétrique_INFÉRIEUR - sous Niveau: <aucun>
Pset_WallCommon - Reference: default [70,00] (..\VERTICALES\Default\)
Name | In | Description | __RECOGNIZE__, ID = IFC_Pset_Caractéristiques, ID | TPLG | TPLG_OD | 0, Crc = 1, Crc = 2, Crc | Alignment | ExternalFace | Numérotation | Numéro niveau | Titre niveau | Épaisseur VARIABLE | Longueur (cm) = NominalLength (cm) | IFC_Pset_Géométrie, Hauteur (cm) = IFC_Pset_Géométrie_P1 (POINT initial), Hauteur (cm) = IFC_Pset_Géométrie_P2 (POINT final), Hauteur (cm) = NominalHeight (cm) | IFC_Pset_Géométrie, Cote (cm) = IFC_Pset_Géométrie_P1 (POINT initial), Cote (cm) = IFC_Pset_Géométrie_P2 (POINT final), Cote (cm) = IFC_Pset_Système de Référence Altimétrique_INFÉRIEUR, delta (cm) = IFC_Pset_Système de Référence Altimétrique_INFÉRIEUR, delta (P1) (cm) = IFC_Pset_Système de Référence Altimétrique_INFÉRIEUR, delta (P2) (cm) | IFC_Pset_Géométrie_P1 (POINT initial), Angle XY (deg) | IFC_Pset_Géométrie_P2 (POINT final), Angle XY (deg) | IFC_Pset_Système de Référence Altimétrique_SUPÉRIEUR, NIVEAU | IFC_Pset_Système de Référence Altimétrique_SUPÉRIEUR, delta (cm) = IFC_Pset_Système de Référence Altimétrique_SUPÉRIEUR, delta (P1) (cm) = IFC_Pset_Système de Référence Altimétrique_SUPÉRIEUR, delta (P2) (cm) | IFC_Pset_Système de Référence Altimétrique_INFÉRIEUR, NIVEAU | Longueur Pied (cm) = Longueur Tête (cm) | Hauteur Maximale (cm) = Hauteur Minimale (cm) | Surface en Plan (cm2) = Surface Pied (cm2) = Surface Tête (cm2) | Surface de la Paroi (cm2) | Volume (cm3) | Face gauche = Face droite = Face latérale | GrossVolume (cm3) | NetVolume (cm3) | NominalWidth (cm) | GrossFootprintArea (cm2) = NetFootprintArea (cm2) | GrossSideArea (cm2) | NetSideArea (cm2) | Group
Enveloppe 71801 | Rez-de-Jardin | Enveloppe | 71801 | 366 | 9000 | 1977773087 | 1 | 1 | 0153 | 02 | Rez-de-Jardin | no | 162.257 | 291.413 | -1.94511e-11 | 90.3759 | 270.376 | HAUT Rez-de-Jardin (Rez-de-chaussée 1047) | 0.0128504 | Rez-de-Jardin (Rez-de-Jardin 15545) | 162.3 | 291.4 | 1100 | 47300 | 330000 | Ivoire clair | 330988 | 209860 | 7 | 1135.8 | 47284 | 29980 | ...de stratigraphies = default; ...de matériaux et couleurs = Ivoire clair; ...de matériaux et couleurs - 1 = Ivoire clair; ...de matériaux et couleurs - 2 = Ivoire clair
Enveloppe 71973 | Rez-de-Jardin | Enveloppe | 71973 | 366 | 9000 | 1977773087 | 1 | 1 | 0154 | 02 | Rez-de-Jardin | yes | 159.128 | 291.413 | -1.94511e-11 | 90.9575 | 270.958 | HAUT Rez-de-Jardin (Rez-de-chaussée 1047) | 0.0128504 | Rez-de-Jardin (Rez-de-Jardin 15545) | 159.1 | 291.4 | 1300 | 46400 | 370000 | Ivoire clair | 365716 | 365716 | 7.88656 | 1254.97 | 46372.1 | 46372.1 | ...de stratigraphies = default; ...de matériaux et couleurs = Ivoire clair; ...de matériaux et couleurs - 1 = Ivoire clair; ...de matériaux et couleurs - 2 = Ivoire clair
Enveloppe 69994 | Rez-de-Jardin | Enveloppe | 69994 | 366 | 9000 | 1977773087 | 0 | 0 | 0136 | 02 | Rez-de-Jardin | no | 151.641 | 291.413 | -1.94511e-11 | 90.5105 | 270.51 | HAUT Rez-de-Jardin (Rez-de-chaussée 1047) | 0.0128504 | Rez-de-Jardin (Rez-de-Jardin 15545) | 151.6 | 291.4 | 1100 | 44200 | 310000 | Ivoire clair | 309331 | 309331 | 7 | 1061.49 | 44190.1 | 44190.1 | ...de stratigraphies = default; ...de matériaux et couleurs = Ivoire clair; ...de matériaux et couleurs - 1 = Ivoire clair; ...de matériaux et couleurs - 2 = Ivoire clair
Enveloppe 54613 | Rez-de-Jardin | Enveloppe | 54613 | 366 | 9000 | 1977773087 | 1 | 1 | 0096 | 02 | Rez-de-Jardin | no | 28.5013 | 291.413 | -1.94511e-11 | 90.3188 | 270.319 | HAUT Rez-de-Jardin (Rez-de-chaussée 1047) | 0.0128504 | Rez-de-Jardin (Rez-de-Jardin 15545) | 28.5 | 291.4 | 200 | 8300 | 60000 | Ivoire clair | 58139.6 | 58139.6 | 7 | 199.509 | 8305.66 | 8305.66 | ...de stratigraphies = default; ...de matériaux et couleurs = Ivoire clair; ...de matériaux et couleurs - 1 = Ivoire clair; ...de matériaux et couleurs - 2 = Ivoire clair
Enveloppe 54735 | Rez-de-Jardin | Enveloppe | 54735 | 366 | 9000 | 1977773087 | 1 | 1 | 0099 | 02 | Rez-de-Jardin | no | 167.678 | 291.413 | -1.94511e-11 | 90.6963 | 270.696 | HAUT Rez-de-Jardin (Rez-de-chaussée 1047) | 0.0128504 | Rez-de-Jardin (Rez-de-Jardin 15545) | 167.7 | 291.4 | 1200 | 48900 | 340000 | Ivoire clair | 342046 | 342046 | 7 | 1173.75 | 48863.7 | 48863.7 | ...de stratigraphies = default; ...de matériaux et couleurs = Ivoire clair; ...de matériaux et couleurs - 1 = Ivoire clair; ...de matériaux et couleurs - 2 = Ivoire clair
Enveloppe 25072 | Rez-de-chaussée | Enveloppe | 25072 | 366 | 9000 | 1977773087 | 1 | 0 | 0054 | 03 | Rez-de-chaussée | yes | 129.808 | 260 | 0.0128504 | 90.4996 | 270.5 | HAUT Rez-de-chaussée (Niveau 1 2343) | -217.783 | Rez-de-chaussée (Rez-de-chaussée 1047) | 129.8 | 260 | 1000 | 33700 | 240000 | Ivoire clair | 249993 | 107922 | 7.40719 | 961.51 | 33750 | 14592 | ...de stratigraphies = default; ...de matériaux et couleurs = Ivoire clair; ...de matériaux et couleurs - 1 = Ivoire clair; ...de matériaux et couleurs - 2 = Ivoire clair
Enveloppe 30316 | Rez-de-chaussée | Enveloppe | 30316 | 366 | 9000 | 1977773087 | 0 | 0 | 0062 | 03 | Rez-de-chaussée | no | 129.014 | 264.987 | 0.0128504 | 90.3156 | 270.316 | HAUT Rez-de-chaussée (Niveau 1 2343) | -212.795 | Rez-de-chaussée (Rez-de-chaussée 1047) | 129 | 265 | 900 | 34200 | 240000 | Ivoire clair | 239309 | 104586 | 7 | 903.098 | 34187.1 | 14940.9 | ...de stratigraphies = default; ...de matériaux et couleurs = Ivoire clair; ...de matériaux et couleurs - 1 = Ivoire clair; ...de matériaux et couleurs - 2 = Ivoire clair
Enveloppe 3061 | Rez-de-chaussée | Enveloppe | 3061 | 366 | 9000 | 1977773087 | 0 | 0 | 0019 | 03 | Rez-de-chaussée | no | 89.8928 | 352.895 | 0.0128504 | 179.627 | 359.627 | HAUT Rez-de-chaussée (Niveau 1 2343) | -124.887 | Rez-de-chaussée (Rez-de-chaussée 1047) | 89.9 | 352.9 | 600 | 31700 | 220000 | Ivoire clair | 222059 | 104135 | 7 | 629.25 | 31722.8 | 14876.4 | ...de stratigraphies = default; ...de matériaux et couleurs = Ivoire clair; ...de matériaux et couleurs - 1 = Ivoire clair; ...de matériaux et couleurs - 2 = Ivoire clair
Enveloppe 93039 | Niveau 1 | Enveloppe | 93039 | 366 | 9000 | 1977773087 | 0 | 0 | 0198 | 04 | Niveau 1 | no | 150.66 | 376.102 | 0.0128504 | 0.458835 | 180.459 | HAUT Niveau 1 (Niveau 2 13545) | 0 | Niveau 1 (Niveau 1 2343) | 150.7 | 376.1 | 1100 | 56700 | 400000 | Ivoire clair | 396645 | 134055 | 7 | 1054.62 | 56663.5 | 19150.7 | ...de stratigraphies = default; ...de matériaux et couleurs = Ivoire clair; ...de matériaux et couleurs - 1 = Ivoire clair; ...de matériaux et couleurs - 2 = Ivoire clair
Enveloppe 92734 | Niveau 1 | Enveloppe | 92734 | 366 | 9000 | 1977773087 | 0 | 1 | 0191 | 04 | Niveau 1 | no | 102.379 | 376.102 | 0.0128504 | 0.22243 | 180.222 | HAUT Niveau 1 (Niveau 2 13545) | 0 | Niveau 1 (Niveau 1 2343) | 102.4 | 376.1 | 700 | 38500 | 270000 | Ivoire clair | 269534 | 138032 | 7 | 716.652 | 38504.9 | 19718.9 | ...de stratigraphies = default; ...de matériaux et couleurs = Ivoire clair; ...de matériaux et couleurs - 1 = Ivoire clair; ...de matériaux et couleurs - 2 = Ivoire clair
Enveloppe 121320 | Niveau 1 | Enveloppe | 121320 | 366 | 9000 | 1977773087 | 0 | 0 | 0294 | 04 | Niveau 1 | no | 112.485 | 237 | 0.0128504 | 90.174 | 270.174 | HAUT Niveau 1 (Niveau 2 13545) | -139.102 | Niveau 1 (Niveau 1 2343) | 112.5 | 237 | 800 | 26700 | 190000 | Ivoire clair | 186613 | 65382.9 | 7 | 787.398 | 26659.1 | 9340.41 | ...de stratigraphies = default; ...de matériaux et couleurs = Ivoire clair; ...de matériaux et couleurs - 1 = Ivoire clair; ...de matériaux et couleurs - 2 = Ivoire clair
Enveloppe 119134 | Niveau 1 | Enveloppe | 119134 | 366 | 9000 | 1977773087 | 1 | 0 | 0285 | 04 | Niveau 1 | no | 149.906 | 376.102 | 0.0128504 | 90.3835 | 270.384 | HAUT Niveau 1 (Niveau 2 13545) | 0 | Niveau 1 (Niveau 1 2343) | 149.9 | 376.1 | 1000 | 56400 | 390000 | Ivoire clair | 394658 | 253766 | 7 | 1049.34 | 56379.8 | 36252.3 | ...de stratigraphies = default; ...de matériaux et couleurs = Ivoire clair; ...de matériaux et couleurs - 1 = Ivoire clair; ...de matériaux et couleurs - 2 = Ivoire clair
Enveloppe 103324 | Niveau 1 | Enveloppe | 103324 | 366 | 9000 | 1977773087 | 0 | 0 | 0254 | 04 | Niveau 1 | no | 83.7887 | 376.102 | 0.0128504 | 91.0688 | 271.069 | HAUT Niveau 1 (Niveau 2 13545) | 0 | Niveau 1 (Niveau 1 2343) | 83.8 | 376.1 | 600 | 31500 | 220000 | Ivoire clair | 220592 | 220592 | 7 | 586.521 | 31513.1 | 31513.1 | ...de stratigraphies = default; ...de matériaux et couleurs = Ivoire clair; ...de matériaux et couleurs - 1 = Ivoire clair; ...de matériaux et couleurs - 2 = Ivoire clair
Enveloppe 133213 | Niveau 1 | Enveloppe | 133213 | 366 | 9000 | 1977773087 | 1 | 0 | 0308 | 04 | Niveau 1 | no | 38.3147 | 376.102 | 0.0128504 | 178.695 | 358.695 | HAUT Niveau 1 (Niveau 2 13545) | 0 | Niveau 1 (Niveau 1 2343) | 38.3 | 376.1 | 300 | 14400 | 100000 | Ivoire clair | 100872 | 100872 | 7 | 268.203 | 14410.2 | 14410.2 | ...de stratigraphies = default; ...de matériaux et couleurs = Ivoire clair; ...de matériaux et couleurs - 1 = Ivoire clair; ...de matériaux et couleurs - 2 = Ivoire clair
Enveloppe 132860 | Niveau 1 | Enveloppe | 132860 | 366 | 9000 | 1977773087 | 0 | 0 | 0306 | 04 | Niveau 1 | no | 27.1497 | 376.102 | 0.0128504 | 48.3504 | 228.35 | HAUT Niveau 1 (Niveau 2 13545) | 0 | Niveau 1 (Niveau 1 2343) | 27.1 | 376.1 | 200 | 10200 | 70000 | Ivoire clair | 71477.4 | 71477.4 | 7 | 190.048 | 10211.1 | 10211.1 | ...de stratigraphies = default; ...de matériaux et couleurs = Ivoire clair; ...de matériaux et couleurs - 1 = Ivoire clair; ...de matériaux et couleurs - 2 = Ivoire clair
Enveloppe 128735 | Niveau 1 | Enveloppe | 128735 | 366 | 9000 | 1977773087 | 1 | 0 | 0299 | 04 | Niveau 1 | no | 117.772 | 233.487 | 0.0128504 | 89.8913 | 269.891 | HAUT Niveau 1 (Niveau 2 13545) | -142.615 | Niveau 1 (Niveau 1 2343) | 117.8 | 233.5 | 800 | 27500 | 190000 | Ivoire clair | 192489 | 69323.5 | 7 | 824.407 | 27498.4 | 9903.36 | ...de stratigraphies = default; ...de matériaux et couleurs = Ivoire clair; ...de matériaux et couleurs - 1 = Ivoire clair; ...de matériaux et couleurs - 2 = Ivoire clair
Enveloppe 132385 | Niveau 1 | Enveloppe | 132385 | 366 | 9000 | 1977773087 | 1 | 0 | 0303 | 04 | Niveau 1 | no | 193.916 | 376.102 | 0.0128504 | 89.5813 | 269.581 | HAUT Niveau 1 (Niveau 2 13545) | 0 | Niveau 1 (Niveau 1 2343) | 193.9 | 376.1 | 1400 | 72900 | 510000 | Ivoire clair | 510526 | 392975 | 7 | 1357.41 | 72932.2 | 56139.3 | ...de stratigraphies = default; ...de matériaux et couleurs = Ivoire clair; ...de matériaux et couleurs - 1 = Ivoire clair; ...de matériaux et couleurs - 2 = Ivoire clair
Enveloppe 120794 | Niveau 1 | Enveloppe | 120794 | 366 | 9000 | 1977773087 | 1 | 0 | 0291 | 04 | Niveau 1 | no | 381.43 | 376.102 | 0.0128504 | 0.236858 | 180.237 | HAUT Niveau 1 (Niveau 2 13545) | 0 | Niveau 1 (Niveau 1 2343) | 381.4 | 376.1 | 2700 | 143400 | 1000000 | Ivoire clair | 1004196 | 534943 | 7 | 2670.01 | 143457 | 76420.4 | ...de stratigraphies = default; ...de matériaux et couleurs = Ivoire clair; ...de matériaux et couleurs - 1 = Ivoire clair; ...de matériaux et couleurs - 2 = Ivoire clair
Enveloppe 95537 | Niveau 1 | Enveloppe | 95537 | 366 | 9000 | 1977773087 | 1 | 0 | 0245 | 04 | Niveau 1 | no | 159.25 | 208.102 | 0.0128504 | 0.0515293 | 180.052 | HAUT Niveau 1 (Niveau 2 13545) | -168 | Niveau 1 (Niveau 1 2343) | 159.3 | 208.1 | 1200 | 33200 | 230000 | Ivoire clair | 231982 | 19405.8 | 7 | 1114.75 | 33140.3 | 2772.25 | ...de stratigraphies = default; ...de matériaux et couleurs = Ivoire clair; ...de matériaux et couleurs - 1 = Ivoire clair; ...de matériaux et couleurs - 2 = Ivoire clair
Enveloppe 177079 | Niveau 2 | Enveloppe | 177079 | 366 | 9000 | 1977773087 | 1 | 0 | 0457 | 05 | Niveau 2 | no | 50.7055 | 294.702 | 1.42109e-12 | 2.73208 | 182.732 | HAUT Mezzanine (Couverture 2134) | -220 | Niveau 2 (Niveau 2 13545) | 50.7 | 294.7 | 400 | 14900 | 100000 | Ivoire clair | 104601 | 104601 | 7 | 354.938 | 14943 | 14943 | ...de stratigraphies = default; ...de matériaux et couleurs = Ivoire clair; ...de matériaux et couleurs - 1 = Ivoire clair; ...de matériaux et couleurs - 2 = Ivoire clair
Enveloppe 161866 | Niveau 2 | Enveloppe | 161866 | 366 | 9000 | 1977773087 | 0 | 0 | 0388 | 05 | Niveau 2 | no | 32.8473 | 235 | 1.42109e-12 | 136.15 | 316.15 | HAUT Niveau 2 (Mezzanine 49003) | 0 | Niveau 2 (Niveau 2 13545) | 32.8 | 235 | 200 | 7700 | 50000 | Ivoire clair | 54033.8 | 54033.8 | 7 | 229.931 | 7719.12 | 7719.12 | ...de stratigraphies = default; ...de matériaux et couleurs = Ivoire clair; ...de matériaux et couleurs - 1 = Ivoire clair; ...de matériaux et couleurs - 2 = Ivoire clair
Muret 783767 | Couverture | _MRT_Muret | 783767 | 441 | 9010 | 1164012461 | 1 | 0 | 16 | 07 | Couverture | no | 103.923 | 385 | -270 | 89.2819 | 269.282 | (Couverture 2134 <aucun>) | 115 | Couverture (Couverture 2134) | 103.9 | 385 | 700 | 40000 | 280000 | Brique (01) | 280074 | 280074 | 7 | 727.464 | 40010.5 | 40010.5 | ...de stratigraphies = default; ...de matériaux et couleurs = Brique (01); ...de matériaux et couleurs - 1 = Brique (01); ...de matériaux et couleurs - 2 = Brique (01)
Muret 793926 | Couverture | _MRT_Muret | 793926 | 441 | 9010 | 1164012461 | 1 | 0 | 17 | 07 | Couverture | no | 50.2 | 345 | -240 | 88.9515 | 268.952 | (Couverture 2134 <aucun>) | 105 | Couverture (Couverture 2134) | 50.2 | 345 | 400 | 17300 | 120000 | Brique (01) | 121233 | 121233 | 7 | 351.4 | 17319 | 17319 | ...de stratigraphies = default; ...de matériaux et couleurs = Brique (01); ...de matériaux et couleurs - 1 = Brique (01); ...de matériaux et couleurs - 2 = Brique (01)
Muret 794001 | Couverture | _MRT_Muret | 794001 | 441 | 9010 | 1164012461 | 0 | 0 | 18 | 07 | Couverture | no | 122.669 | 345 | -240 | 179.972 | 359.972 | (Couverture 2134 <aucun>) | 105 | Couverture (Couverture 2134) | 122.7 | 345 | 900 | 42300 | 300000 | Brique (01) | 296246 | 296246 | 7 | 858.683 | 42320.8 | 42320.8 | ...de stratigraphies = default; ...de matériaux et couleurs = Brique (01); ...de matériaux et couleurs - 1 = Brique (01); ...de matériaux et couleurs - 2 = Brique (01)
Muret 783708 | Couverture | _MRT_Muret | 783708 | 441 | 9010 | 1164012461 | 0 | 0 | 13 | 07 | Couverture | no | 31.8893 | 385 | -270 | 178.893 | 358.893 | (Couverture 2134 <aucun>) | 115 | Couverture (Couverture 2134) | 31.9 | 385 | 200 | 12300 | 90000 | Brique (01) | 85941.8 | 85941.8 | 7 | 223.225 | 12277.4 | 12277.4 | ...de stratigraphies = default; ...de matériaux et couleurs = Brique (01); ...de matériaux et couleurs - 1 = Brique (01); ...de matériaux et couleurs - 2 = Brique (01)
Muret 783751 | Couverture | _MRT_Muret | 783751 | 441 | 9010 | 1164012461 | 0 | 0 | 14 | 07 | Couverture | no | 103.223 | 365 | -250 | 89.2526 | 269.253 | (Couverture 2134 <aucun>) | 115 | Couverture (Couverture 2134) | 103.2 | 365 | 700 | 37700 | 260000 | Brique (01) | 263736 | 263736 | 7 | 722.564 | 37676.6 | 37676.6 | ...de stratigraphies = default; ...de matériaux et couleurs = Brique (01); ...de matériaux et couleurs - 1 = Brique (01); ...de matériaux et couleurs - 2 = Brique (01)
Muret 783762 | Couverture | _MRT_Muret | 783762 | 441 | 9010 | 1164012461 | 0 | 0 | 15 | 07 | Couverture | no | 31.8372 | 385 | -270 | 0.143707 | 180.144 | (Couverture 2134 <aucun>) | 115 | Couverture (Couverture 2134) | 31.8 | 385 | 200 | 12200 | 90000 | Brique (01) | 85801.2 | 85801.2 | 7 | 222.86 | 12257.3 | 12257.3 | ...de stratigraphies = default; ...de matériaux et couleurs = Brique (01); ...de matériaux et couleurs - 1 = Brique (01); ...de matériaux et couleurs - 2 = Brique (01)
Muret 794006 | Couverture | _MRT_Muret | 794006 | 441 | 9010 | 1164012461 | 0 | 0 | 19 | 07 | Couverture | no | 50.1837 | 345 | -240 | 88.7045 | 268.705 | (Couverture 2134 <aucun>) | 105 | Couverture (Couverture 2134) | 50.2 | 345 | 400 | 17300 | 120000 | Brique (01) | 121194 | 121194 | 7 | 351.286 | 17313.4 | 17313.4 | ...de stratigraphies = default; ...de matériaux et couleurs = Brique (01); ...de matériaux et couleurs - 1 = Brique (01); ...de matériaux et couleurs - 2 = Brique (01)
Muret 794011 | Couverture | _MRT_Muret | 794011 | 441 | 9010 | 1164012461 | 1 | 0 | 20 | 07 | Couverture | no | 122.45 | 275 | -170 | 179.981 | 359.981 | (Couverture 2134 <aucun>) | 105 | Couverture (Couverture 2134) | 122.5 | 275 | 900 | 33700 | 240000 | Brique (01) | 235717 | 235717 | 7 | 857.152 | 33673.8 | 33673.8 | ...de stratigraphies = default; ...de matériaux et couleurs = Brique (01); ...de matériaux et couleurs - 1 = Brique (01); ...de matériaux et couleurs - 2 = Brique (01)
Muret 782793 | Couverture | _MRT_Muret | 782793 | 441 | 9010 | 1164012461 | 0 | 0 | 04 | 07 | Couverture | no | 84.9092 | 360 | -260 | 43.4518 | 223.452 | (Couverture 2134 <aucun>) | 100 | Couverture (Couverture 2134) | 84.9 | 360 | 600 | 30600 | 210000 | Brique (01) | 213971 | 213971 | 7 | 594.365 | 30567.3 | 30567.3 | ...de stratigraphies = default; ...de matériaux et couleurs = Brique (01); ...de matériaux et couleurs - 1 = Brique (01); ...de matériaux et couleurs - 2 = Brique (01)
Muret 782754 | Couverture | _MRT_Muret | 782754 | 441 | 9010 | 1164012461 | 1 | 0 | 01 | 07 | Couverture | no | 46.0272 | 360 | -260 | 138.522 | 318.522 | (Couverture 2134 <aucun>) | 100 | Couverture (Couverture 2134) | 46 | 360 | 300 | 16600 | 120000 | Brique (01) | 115989 | 115989 | 7 | 322.191 | 16569.8 | 16569.8 | ...de stratigraphies = default; ...de matériaux et couleurs = Brique (01); ...de matériaux et couleurs - 1 = Brique (01); ...de matériaux et couleurs - 2 = Brique (01)
Muret 782770 | Couverture | _MRT_Muret | 782770 | 441 | 9010 | 1164012461 | 0 | 0 | 02 | 07 | Couverture | no | 49.6827 | 360 | -260 | 134.393 | 314.393 | (Couverture 2134 <aucun>) | 100 | Couverture (Couverture 2134) | 49.7 | 360 | 300 | 17900 | 130000 | Brique (01) | 125200 | 125200 | 7 | 347.779 | 17885.8 | 17885.8 | ...de stratigraphies = default; ...de matériaux et couleurs = Brique (01); ...de matériaux et couleurs - 1 = Brique (01); ...de matériaux et couleurs - 2 = Brique (01)
Muret 782792 | Couverture | _MRT_Muret | 782792 | 441 | 9010 | 1164012461 | 1 | 0 | 03 | 07 | Couverture | no | 87.7875 | 340 | -240 | 45.4306 | 225.431 | (Couverture 2134 <aucun>) | 100 | Couverture (Couverture 2134) | 87.8 | 340 | 600 | 29900 | 210000 | Brique (01) | 208934 | 208934 | 7 | 614.512 | 29847.7 | 29847.7 | ...de stratigraphies = default; ...de matériaux et couleurs = Brique (01); ...de matériaux et couleurs - 1 = Brique (01); ...de matériaux et couleurs - 2 = Brique (01)

# IfcWallStandardCase: default 72, Enveloppe 54734
In: Rez-de-Jardin
Type - Material: <aucun> 7.2 cm
Description: Enveloppe; Group: ...de stratigraphies = default; ...de matériaux et couleurs = Ivoire clair; ...de matériaux et couleurs - 1 = Ivoire clair; ...de matériaux et couleurs - 2 = Ivoire clair
__RECOGNIZE__ - ID: 54734; TPLG: 366; TPLG_OD: 9000; GENERATE: 1
CTLG_EXTERNAL_LINK - 0, DocType: 2; 0, Tag: 0; 0, Crc: 1977773087; 1, DocType: 2; 1, Tag: 100; 1, Crc: 1977773087; 2, DocType: 2; 2, Tag: 200; 2, Crc: 1977773087; 3, DocType: 9; 3, Tag: 0; 3, Crc: -1109369977
IFC_PSET_PolygonOffset - polygonOffsetFactor: 2; polygonOffsetUnits: 2
IFC_Pset_Alignment - Alignment: 0
IFC_Pset_Strat_Detail_Align - ExternalFace: 1
IFC_Pset_Caractéristiques - ID: 54734; Numérotation: 0098; Numéro niveau: 02; Titre niveau: Rez-de-Jardin; Stratigraphie: default [72,00]; Épaisseur: 7.2 cm; Épaisseur VARIABLE: no
IFC_Pset_Caractéristiques_FRUIT - Fruit: no; Taille: 0 cm
IFC_Pset_Géométrie - Forme en Élévation: rectangle; Longueur: 162.648 cm; Hauteur: 291.413 cm; Cote: -1.94511e-11 cm
IFC_Pset_Géométrie_P1 (POINT initial) - Hauteur: 291.413 cm; Cote: -1.94511e-11 cm; Angle XY: 90.3188 deg
IFC_Pset_Géométrie_P2 (POINT final) - Hauteur: 291.413 cm; Cote: -1.94511e-11 cm; Angle XY: 270.319 deg
IFC_Pset_Système de Référence Altimétrique_SUPÉRIEUR - NIVEAU: HAUT Rez-de-Jardin (Rez-de-chaussée 1047); delta: 0.0128504 cm; delta (P1): 0.0128504 cm; delta (P2): 0.0128504 cm; sous Niveau: <aucun>
IFC_Pset_Système de Référence Altimétrique_INFÉRIEUR - NIVEAU: Rez-de-Jardin (Rez-de-Jardin 15545); delta: -1.94511e-11 cm; delta (P1): -1.94511e-11 cm; delta (P2): -1.94511e-11 cm; sous Niveau: <aucun>
IFC_Pset_Données Métré - Longueur Pied: 162.6 cm; Longueur Tête: 162.6 cm; Hauteur Maximale: 291.4 cm; Hauteur Minimale: 291.4 cm; Surface en Plan: 1100 cm2; Surface Pied: 1100 cm2; Surface Tête: 1100 cm2; Surface de la Paroi: 47400 cm2; Volume: 330000 cm3
IFC_Pset_Matériaux - Face gauche: Ivoire clair; Face droite: Ivoire clair; Face latérale: Ivoire clair
Pset_WallCommon - Reference: default [72,00] (..\VERTICALES\Default\)
BaseQuantities - GrossVolume: 341263 cm3; NetVolume: 341263 cm3; NominalLength: 162.648 cm; NominalWidth: 7.2 cm; NominalHeight: 291.413 cm; GrossFootprintArea: 1171.06 cm2; NetFootprintArea: 1171.06 cm2; GrossSideArea: 47397.7 cm2; NetSideArea: 47397.7 cm2

# IfcWallStandardCase: default 725 (4)
In: Rez-de-Jardin
Type - Material: <aucun> 72.5 cm
Description: Enveloppe; Group: ...de stratigraphies = default; ...de matériaux et couleurs = Ivoire clair; ...de matériaux et couleurs - 1 = Ivoire clair; ...de matériaux et couleurs - 2 = Ivoire clair
__RECOGNIZE__ - TPLG: 366; TPLG_OD: 9000; GENERATE: 1
CTLG_EXTERNAL_LINK - 0, DocType: 2; 0, Tag: 0; 0, Crc: 1977773087; 1, DocType: 2; 1, Tag: 100; 1, Crc: 1977773087; 2, DocType: 2; 2, Tag: 200; 2, Crc: 1977773087; 3, DocType: 9; 3, Tag: 0; 3, Crc: -275958153
IFC_PSET_PolygonOffset - polygonOffsetFactor: 2; polygonOffsetUnits: 2
IFC_Pset_Strat_Detail_Align - ExternalFace: 1
IFC_Pset_Caractéristiques - Numéro niveau: 02; Titre niveau: Rez-de-Jardin; Stratigraphie: default [725,00]; Épaisseur: 72.5 cm
IFC_Pset_Caractéristiques_FRUIT - Fruit: no; Taille: 0 cm
IFC_Pset_Géométrie - Forme en Élévation: rectangle; Hauteur: 291.413 cm; Cote: -1.94511e-11 cm
IFC_Pset_Géométrie_P1 (POINT initial) - Hauteur: 291.413 cm; Cote: -1.94511e-11 cm
IFC_Pset_Géométrie_P2 (POINT final) - Hauteur: 291.413 cm; Cote: -1.94511e-11 cm
IFC_Pset_Système de Référence Altimétrique_SUPÉRIEUR - NIVEAU: HAUT Rez-de-Jardin (Rez-de-chaussée 1047); delta: 0.0128504 cm; delta (P1): 0.0128504 cm; delta (P2): 0.0128504 cm; sous Niveau: <aucun>
IFC_Pset_Système de Référence Altimétrique_INFÉRIEUR - NIVEAU: Rez-de-Jardin (Rez-de-Jardin 15545); delta: -1.94511e-11 cm; delta (P1): -1.94511e-11 cm; delta (P2): -1.94511e-11 cm; sous Niveau: <aucun>
IFC_Pset_Données Métré - Hauteur Maximale: 291.4 cm; Hauteur Minimale: 291.4 cm
IFC_Pset_Matériaux - Face gauche: Ivoire clair; Face droite: Ivoire clair; Face latérale: Ivoire clair
Pset_WallCommon - Reference: default [725,00] (..\VERTICALES\Default\)
BaseQuantities - NominalHeight: 291.413 cm
Name | __RECOGNIZE__, ID = IFC_Pset_Caractéristiques, ID | Alignment | Numérotation | Épaisseur VARIABLE | Longueur (cm) = NominalLength (cm) | IFC_Pset_Géométrie_P1 (POINT initial), Angle XY (deg) | IFC_Pset_Géométrie_P2 (POINT final), Angle XY (deg) | Longueur Pied (cm) = Longueur Tête (cm) | Surface en Plan (cm2) = Surface Pied (cm2) = Surface Tête (cm2) | Surface de la Paroi (cm2) | Volume (cm3) | GrossVolume (cm3) | NetVolume (cm3) | NominalWidth (cm) | GrossFootprintArea (cm2) = NetFootprintArea (cm2) | GrossSideArea (cm2) | NetSideArea (cm2)
Enveloppe 57679 | 57679 | 1 | 0112 | yes | 250.388 | 0.259129 | 180.259 | 250.4 | 18500 | 73000 | 5400000 | 5393672 | 5393672 | 73.92 | 18508.7 | 72966.4 | 72966.4
Enveloppe 65039 | 65039 | 0 | 0120 | yes | 176.878 | 1.27808 | 181.278 | 176.9 | 13100 | 51500 | 3810000 | 3827226 | 2176285 | 74.2506 | 13133.3 | 51544.7 | 29544.1
Enveloppe 54039 | 54039 | 0 | 0091 | yes | 36.4529 | 88.9668 | 268.967 | 36.5 | 2700 | 10600 | 780000 | 777951 | 777951 | 73.2336 | 2669.58 | 10622.9 | 10622.9
Enveloppe 64999 | 64999 | 1 | 0119 | no | 212.886 | 179.917 | 359.917 | 212.9 | 15600 | 62000 | 4530000 | 4497743 | 4497743 | 72.5 | 15434.2 | 62037.8 | 62037.8

# IfcWallStandardCase: default 73.4207077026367, Enveloppe 3325
In: Rez-de-chaussée
Type - Material: <aucun> 7.34207 cm
Description: Enveloppe; Group: ...de stratigraphies = default; ...de matériaux et couleurs = Ivoire clair; ...de matériaux et couleurs - 1 = Ivoire clair; ...de matériaux et couleurs - 2 = Ivoire clair
__RECOGNIZE__ - ID: 3325; TPLG: 366; TPLG_OD: 9000; GENERATE: 1
CTLG_EXTERNAL_LINK - 0, DocType: 2; 0, Tag: 0; 0, Crc: 1977773087; 1, DocType: 2; 1, Tag: 100; 1, Crc: 1977773087; 2, DocType: 2; 2, Tag: 200; 2, Crc: 1977773087; 3, DocType: 9; 3, Tag: 0; 3, Crc: -1387146722
IFC_PSET_PolygonOffset - polygonOffsetFactor: 2; polygonOffsetUnits: 2
IFC_Pset_Alignment - Alignment: 0
IFC_Pset_Strat_Detail_Align - ExternalFace: 0
IFC_Pset_Caractéristiques - ID: 3325; Numérotation: 0027; Numéro niveau: 03; Titre niveau: Rez-de-chaussée; Stratigraphie: default [73,42]; Épaisseur: 7.34 cm; Épaisseur VARIABLE: no
IFC_Pset_Caractéristiques_FRUIT - Fruit: no; Taille: 0 cm
IFC_Pset_Géométrie - Forme en Élévation: rectangle; Longueur: 139.971 cm; Hauteur: 247.862 cm; Cote: 0.0128504 cm
IFC_Pset_Géométrie_P1 (POINT initial) - Hauteur: 247.862 cm; Cote: 0.0128504 cm; Angle XY: 90.3027 deg
IFC_Pset_Géométrie_P2 (POINT final) - Hauteur: 247.862 cm; Cote: 0.0128504 cm; Angle XY: 270.303 deg
IFC_Pset_Système de Référence Altimétrique_SUPÉRIEUR - NIVEAU: HAUT Rez-de-chaussée (Niveau 1 2343); delta: -229.921 cm; delta (P1): -229.921 cm; delta (P2): -229.921 cm; sous Niveau: <aucun>
IFC_Pset_Système de Référence Altimétrique_INFÉRIEUR - NIVEAU: Rez-de-chaussée (Rez-de-chaussée 1047); delta: 0.0128504 cm; delta (P1): 0.0128504 cm; delta (P2): 0.0128504 cm; sous Niveau: <aucun>
IFC_Pset_Données Métré - Longueur Pied: 140 cm; Longueur Tête: 140 cm; Hauteur Maximale: 247.9 cm; Hauteur Minimale: 247.9 cm; Surface en Plan: 1000 cm2; Surface Pied: 1000 cm2; Surface Tête: 1000 cm2; Surface de la Paroi: 34700 cm2; Volume: 240000 cm3
IFC_Pset_Matériaux - Face gauche: Ivoire clair; Face droite: Ivoire clair; Face latérale: Ivoire clair
Pset_WallCommon - Reference: default [73,42] (..\VERTICALES\Default\)
BaseQuantities - GrossVolume: 254722 cm3; NetVolume: 254722 cm3; NominalLength: 139.971 cm; NominalWidth: 7.34207 cm; NominalHeight: 247.862 cm; GrossFootprintArea: 1027.68 cm2; NetFootprintArea: 1027.68 cm2; GrossSideArea: 34693.5 cm2; NetSideArea: 34693.5 cm2

# IfcWallStandardCase: default 730 (3)
In: Rez-de-Jardin
Type - Material: <aucun> 73 cm
Description: Enveloppe; Group: ...de stratigraphies = default; ...de matériaux et couleurs = Ivoire clair; ...de matériaux et couleurs - 1 = Ivoire clair; ...de matériaux et couleurs - 2 = Ivoire clair
__RECOGNIZE__ - TPLG: 366; TPLG_OD: 9000; GENERATE: 1
CTLG_EXTERNAL_LINK - 0, DocType: 2; 0, Tag: 0; 0, Crc: 1977773087; 1, DocType: 2; 1, Tag: 100; 1, Crc: 1977773087; 2, DocType: 2; 2, Tag: 200; 2, Crc: 1977773087; 3, DocType: 9; 3, Tag: 0; 3, Crc: -406584189
IFC_PSET_PolygonOffset - polygonOffsetFactor: 2; polygonOffsetUnits: 2
IFC_Pset_Strat_Detail_Align - ExternalFace: 1
IFC_Pset_Caractéristiques - Numéro niveau: 02; Titre niveau: Rez-de-Jardin; Stratigraphie: default [730,00]; Épaisseur: 73 cm
IFC_Pset_Caractéristiques_FRUIT - Fruit: no; Taille: 0 cm
IFC_Pset_Géométrie - Forme en Élévation: rectangle; Hauteur: 291.413 cm; Cote: -1.94511e-11 cm
IFC_Pset_Géométrie_P1 (POINT initial) - Hauteur: 291.413 cm; Cote: -1.94511e-11 cm
IFC_Pset_Géométrie_P2 (POINT final) - Hauteur: 291.413 cm; Cote: -1.94511e-11 cm
IFC_Pset_Système de Référence Altimétrique_SUPÉRIEUR - NIVEAU: HAUT Rez-de-Jardin (Rez-de-chaussée 1047); delta: 0.0128504 cm; delta (P1): 0.0128504 cm; delta (P2): 0.0128504 cm; sous Niveau: <aucun>
IFC_Pset_Système de Référence Altimétrique_INFÉRIEUR - NIVEAU: Rez-de-Jardin (Rez-de-Jardin 15545); delta: -1.94511e-11 cm; delta (P1): -1.94511e-11 cm; delta (P2): -1.94511e-11 cm; sous Niveau: <aucun>
IFC_Pset_Données Métré - Hauteur Maximale: 291.4 cm; Hauteur Minimale: 291.4 cm
IFC_Pset_Matériaux - Face gauche: Ivoire clair; Face droite: Ivoire clair; Face latérale: Ivoire clair
Pset_WallCommon - Reference: default [730,00] (..\VERTICALES\Default\)
BaseQuantities - NominalHeight: 291.413 cm
Name | __RECOGNIZE__, ID = IFC_Pset_Caractéristiques, ID | Alignment | Numérotation | Épaisseur VARIABLE | Longueur (cm) = NominalLength (cm) | IFC_Pset_Géométrie_P1 (POINT initial), Angle XY (deg) | IFC_Pset_Géométrie_P2 (POINT final), Angle XY (deg) | Longueur Pied (cm) = Longueur Tête (cm) | Surface en Plan (cm2) = Surface Pied (cm2) = Surface Tête (cm2) | Surface de la Paroi (cm2) | Volume (cm3) | GrossVolume (cm3) | NetVolume (cm3) | NominalWidth (cm) | GrossFootprintArea (cm2) = NetFootprintArea (cm2) | GrossSideArea (cm2) | NetSideArea (cm2)
Enveloppe 65369 | 65369 | 1 | 0121 | no | 183.852 | 0.111666 | 180.112 | 183.9 | 13400 | 53600 | 3910000 | 3911104 | 919222 | 73 | 13421.2 | 53576.8 | 12592.1
Enveloppe 55859 | 55859 | 0 | 0105 | yes | 171.852 | 89.9398 | 269.94 | 171.9 | 12700 | 50100 | 3710000 | 3704553 | 3704553 | 73.9727 | 12712.4 | 50080 | 50080
Enveloppe 70969 | 70969 | 1 | 0145 | no | 284.252 | 0.322235 | 180.322 | 284.3 | 20800 | 82800 | 6040000 | 6046946 | 6046946 | 73 | 20750.4 | 82834.9 | 82834.9

# IfcWallStandardCase: default 735 (5)
In: Rez-de-Jardin
Type - Material: <aucun> 73.5 cm
Description: Enveloppe; Group: ...de stratigraphies = default; ...de matériaux et couleurs = Ivoire clair; ...de matériaux et couleurs - 1 = Ivoire clair; ...de matériaux et couleurs - 2 = Ivoire clair
__RECOGNIZE__ - TPLG: 366; TPLG_OD: 9000; GENERATE: 1
CTLG_EXTERNAL_LINK - 0, DocType: 2; 0, Tag: 0; 0, Crc: 1977773087; 1, DocType: 2; 1, Tag: 100; 1, Crc: 1977773087; 2, DocType: 2; 2, Tag: 200; 2, Crc: 1977773087; 3, DocType: 9; 3, Tag: 0; 3, Crc: 1258438239
IFC_PSET_PolygonOffset - polygonOffsetFactor: 2; polygonOffsetUnits: 2
IFC_Pset_Caractéristiques - Numéro niveau: 02; Titre niveau: Rez-de-Jardin; Stratigraphie: default [735,00]; Épaisseur: 73.5 cm
IFC_Pset_Caractéristiques_FRUIT - Fruit: no; Taille: 0 cm
IFC_Pset_Géométrie - Forme en Élévation: rectangle; Hauteur: 291.413 cm; Cote: -1.94511e-11 cm
IFC_Pset_Géométrie_P1 (POINT initial) - Hauteur: 291.413 cm; Cote: -1.94511e-11 cm
IFC_Pset_Géométrie_P2 (POINT final) - Hauteur: 291.413 cm; Cote: -1.94511e-11 cm
IFC_Pset_Système de Référence Altimétrique_SUPÉRIEUR - NIVEAU: HAUT Rez-de-Jardin (Rez-de-chaussée 1047); delta: 0.0128504 cm; delta (P1): 0.0128504 cm; delta (P2): 0.0128504 cm; sous Niveau: <aucun>
IFC_Pset_Système de Référence Altimétrique_INFÉRIEUR - NIVEAU: Rez-de-Jardin (Rez-de-Jardin 15545); delta: -1.94511e-11 cm; delta (P1): -1.94511e-11 cm; delta (P2): -1.94511e-11 cm; sous Niveau: <aucun>
IFC_Pset_Données Métré - Hauteur Maximale: 291.4 cm; Hauteur Minimale: 291.4 cm
IFC_Pset_Matériaux - Face gauche: Ivoire clair; Face droite: Ivoire clair; Face latérale: Ivoire clair
Pset_WallCommon - Reference: default [735,00] (..\VERTICALES\Default\)
BaseQuantities - NominalHeight: 291.413 cm
Name | __RECOGNIZE__, ID = IFC_Pset_Caractéristiques, ID | Alignment | ExternalFace | Numérotation | Épaisseur VARIABLE | Longueur (cm) = NominalLength (cm) | IFC_Pset_Géométrie_P1 (POINT initial), Angle XY (deg) | IFC_Pset_Géométrie_P2 (POINT final), Angle XY (deg) | Longueur Pied (cm) = Longueur Tête (cm) | Surface en Plan (cm2) = Surface Pied (cm2) = Surface Tête (cm2) | Surface de la Paroi (cm2) | Volume (cm3) | GrossVolume (cm3) | NetVolume (cm3) | NominalWidth (cm) | GrossFootprintArea (cm2) = NetFootprintArea (cm2) | GrossSideArea (cm2) | NetSideArea (cm2)
Enveloppe 70184 | 70184 | 0 | 1 | 0139 | yes | 195.669 | 90.4709 | 270.471 | 195.7 | 14500 | 57000 | 4220000 | 4238633 | 2642403 | 74.335 | 14545.1 | 57020.7 | 35436.4
Enveloppe 57428 | 57428 | 0 | 1 | 0111 | no | 76.3723 | 0.192193 | 180.192 | 76.4 | 5700 | 22300 | 1650000 | 1635810 | 1635810 | 73.5 | 5613.37 | 22255.9 | 22255.9
Enveloppe 55625 | 55625 | 0 | 0 | 0103 | no | 199.62 | 0.188507 | 180.189 | 199.6 | 14800 | 58200 | 4310000 | 4275642 | 2728116 | 73.5 | 14672.1 | 58172 | 37117.2
Enveloppe 53966 | 53966 | 0 | 1 | 0090 | no | 182.016 | 0.304158 | 180.304 | 182.1 | 13500 | 53100 | 3930000 | 3898573 | 2662144 | 73.5 | 13378.2 | 53041.8 | 36219.7
Enveloppe 55598 | 55598 | 1 | 0 | 0102 | yes | 61.4101 | 179.95 | 359.95 | 61.4 | 4500 | 17900 | 1340000 | 1334762 | 1334762 | 74.5856 | 4580.31 | 17895.7 | 17895.7

# IfcWallStandardCase: default 740 (4)
In: Rez-de-Jardin
Type - Material: <aucun> 74 cm
Description: Enveloppe; Group: ...de stratigraphies = default; ...de matériaux et couleurs = Ivoire clair; ...de matériaux et couleurs - 1 = Ivoire clair; ...de matériaux et couleurs - 2 = Ivoire clair
__RECOGNIZE__ - TPLG: 366; TPLG_OD: 9000; GENERATE: 1
CTLG_EXTERNAL_LINK - 0, DocType: 2; 0, Tag: 0; 0, Crc: 1977773087; 1, DocType: 2; 1, Tag: 100; 1, Crc: 1977773087; 2, DocType: 2; 2, Tag: 200; 2, Crc: 1977773087; 3, DocType: 9; 3, Tag: 0; 3, Crc: 1957607397
IFC_PSET_PolygonOffset - polygonOffsetFactor: 2; polygonOffsetUnits: 2
IFC_Pset_Caractéristiques - Numéro niveau: 02; Titre niveau: Rez-de-Jardin; Stratigraphie: default [740,00]; Épaisseur: 74 cm
IFC_Pset_Caractéristiques_FRUIT - Fruit: no; Taille: 0 cm
IFC_Pset_Géométrie - Forme en Élévation: rectangle; Hauteur: 291.413 cm; Cote: -1.94511e-11 cm
IFC_Pset_Géométrie_P1 (POINT initial) - Hauteur: 291.413 cm; Cote: -1.94511e-11 cm
IFC_Pset_Géométrie_P2 (POINT final) - Hauteur: 291.413 cm; Cote: -1.94511e-11 cm
IFC_Pset_Système de Référence Altimétrique_SUPÉRIEUR - NIVEAU: HAUT Rez-de-Jardin (Rez-de-chaussée 1047); delta: 0.0128504 cm; delta (P1): 0.0128504 cm; delta (P2): 0.0128504 cm; sous Niveau: <aucun>
IFC_Pset_Système de Référence Altimétrique_INFÉRIEUR - NIVEAU: Rez-de-Jardin (Rez-de-Jardin 15545); delta: -1.94511e-11 cm; delta (P1): -1.94511e-11 cm; delta (P2): -1.94511e-11 cm; sous Niveau: <aucun>
IFC_Pset_Données Métré - Hauteur Maximale: 291.4 cm; Hauteur Minimale: 291.4 cm
IFC_Pset_Matériaux - Face gauche: Ivoire clair; Face droite: Ivoire clair; Face latérale: Ivoire clair
Pset_WallCommon - Reference: default [740,00] (..\VERTICALES\Default\)
BaseQuantities - NominalHeight: 291.413 cm
Name | __RECOGNIZE__, ID = IFC_Pset_Caractéristiques, ID | Alignment | ExternalFace | Numérotation | Épaisseur VARIABLE | Longueur (cm) = NominalLength (cm) | IFC_Pset_Géométrie_P1 (POINT initial), Angle XY (deg) | IFC_Pset_Géométrie_P2 (POINT final), Angle XY (deg) | Longueur Pied (cm) = Longueur Tête (cm) | Surface en Plan (cm2) = Surface Pied (cm2) = Surface Tête (cm2) | Surface de la Paroi (cm2) | Volume (cm3) | GrossVolume (cm3) = NetVolume (cm3) | NominalWidth (cm) | GrossFootprintArea (cm2) = NetFootprintArea (cm2) | GrossSideArea (cm2) = NetSideArea (cm2)
Enveloppe 78516 | 78516 | 0 | 0 | 0176 | yes | 37.7082 | 90.2312 | 270.231 | 37.7 | 2900 | 11000 | 850000 | 847840 | 77.1559 | 2909.41 | 10988.7
Enveloppe 65426 | 65426 | 1 | 0 | 0123 | no | 121.672 | 179.95 | 359.95 | 121.7 | 9000 | 35500 | 2630000 | 2623797 | 74 | 9003.7 | 35456.7
Enveloppe 70598 | 70598 | 0 | 0 | 0140 | no | 120.529 | 0.697824 | 180.698 | 120.5 | 8900 | 35100 | 2600000 | 2599148 | 74 | 8919.12 | 35123.6
Enveloppe 55902 | 55902 | 0 | 1 | 0106 | no | 177.089 | 89.9398 | 269.94 | 177.1 | 13100 | 51600 | 3820000 | 3818844 | 74 | 13104.6 | 51606

# IfcWallStandardCase: default 745, Enveloppe 70923
In: Rez-de-Jardin
Type - Material: <aucun> 74.5 cm
Description: Enveloppe; Group: ...de stratigraphies = default; ...de matériaux et couleurs = Ivoire clair; ...de matériaux et couleurs - 1 = Ivoire clair; ...de matériaux et couleurs - 2 = Ivoire clair
__RECOGNIZE__ - ID: 70923; TPLG: 366; TPLG_OD: 9000; GENERATE: 1
CTLG_EXTERNAL_LINK - 0, DocType: 2; 0, Tag: 0; 0, Crc: 1977773087; 1, DocType: 2; 1, Tag: 100; 1, Crc: 1977773087; 2, DocType: 2; 2, Tag: 200; 2, Crc: 1977773087; 3, DocType: 9; 3, Tag: 0; 3, Crc: 1911354979
IFC_PSET_PolygonOffset - polygonOffsetFactor: 2; polygonOffsetUnits: 2
IFC_Pset_Alignment - Alignment: 0
IFC_Pset_Strat_Detail_Align - ExternalFace: 0
IFC_Pset_Caractéristiques - ID: 70923; Numérotation: 0143; Numéro niveau: 02; Titre niveau: Rez-de-Jardin; Stratigraphie: default [745,00]; Épaisseur: 74.5 cm; Épaisseur VARIABLE: yes
IFC_Pset_Caractéristiques_FRUIT - Fruit: no; Taille: 0 cm
IFC_Pset_Géométrie - Forme en Élévation: rectangle; Longueur: 212.641 cm; Hauteur: 291.413 cm; Cote: -1.94511e-11 cm
IFC_Pset_Géométrie_P1 (POINT initial) - Hauteur: 291.413 cm; Cote: -1.94511e-11 cm; Angle XY: 90.2312 deg
IFC_Pset_Géométrie_P2 (POINT final) - Hauteur: 291.413 cm; Cote: -1.94511e-11 cm; Angle XY: 270.231 deg
IFC_Pset_Système de Référence Altimétrique_SUPÉRIEUR - NIVEAU: HAUT Rez-de-Jardin (Rez-de-chaussée 1047); delta: 0.0128504 cm; delta (P1): 0.0128504 cm; delta (P2): 0.0128504 cm; sous Niveau: <aucun>
IFC_Pset_Système de Référence Altimétrique_INFÉRIEUR - NIVEAU: Rez-de-Jardin (Rez-de-Jardin 15545); delta: -1.94511e-11 cm; delta (P1): -1.94511e-11 cm; delta (P2): -1.94511e-11 cm; sous Niveau: <aucun>
IFC_Pset_Données Métré - Longueur Pied: 212.6 cm; Longueur Tête: 212.6 cm; Hauteur Maximale: 291.4 cm; Hauteur Minimale: 291.4 cm; Surface en Plan: 15900 cm2; Surface Pied: 15900 cm2; Surface Tête: 15900 cm2; Surface de la Paroi: 62000 cm2; Volume: 4650000 cm3
IFC_Pset_Matériaux - Face gauche: Ivoire clair; Face droite: Ivoire clair; Face latérale: Ivoire clair
Pset_WallCommon - Reference: default [745,00] (..\VERTICALES\Default\)
BaseQuantities - GrossVolume: 4631981 cm3; NetVolume: 3024822 cm3; NominalLength: 212.641 cm; NominalWidth: 74.75 cm; NominalHeight: 291.413 cm; GrossFootprintArea: 15894.9 cm2; NetFootprintArea: 15894.9 cm2; GrossSideArea: 61966.3 cm2; NetSideArea: 40505.2 cm2

# IfcWallStandardCase: default 75 (4)
Type - Material: <aucun> 7.5 cm
Description: Enveloppe; Group: ...de stratigraphies = default; ...de matériaux et couleurs = Ivoire clair; ...de matériaux et couleurs - 1 = Ivoire clair; ...de matériaux et couleurs - 2 = Ivoire clair
__RECOGNIZE__ - TPLG: 366; TPLG_OD: 9000; GENERATE: 1
CTLG_EXTERNAL_LINK - 0, DocType: 2; 0, Tag: 0; 0, Crc: 1977773087; 1, DocType: 2; 1, Tag: 100; 1, Crc: 1977773087; 2, DocType: 2; 2, Tag: 200; 2, Crc: 1977773087; 3, DocType: 9; 3, Tag: 0; 3, Crc: 2000412642
IFC_PSET_PolygonOffset - polygonOffsetFactor: 2; polygonOffsetUnits: 2
IFC_Pset_Caractéristiques - Stratigraphie: default [75,00]; Épaisseur: 7.5 cm; Épaisseur VARIABLE: no
IFC_Pset_Caractéristiques_FRUIT - Fruit: no; Taille: 0 cm
IFC_Pset_Géométrie - Forme en Élévation: rectangle
IFC_Pset_Système de Référence Altimétrique_SUPÉRIEUR - sous Niveau: <aucun>
IFC_Pset_Système de Référence Altimétrique_INFÉRIEUR - sous Niveau: <aucun>
IFC_Pset_Matériaux - Face gauche: Ivoire clair; Face droite: Ivoire clair; Face latérale: Ivoire clair
Pset_WallCommon - Reference: default [75,00] (..\VERTICALES\Default\)
BaseQuantities - NominalWidth: 7.5 cm
Name | In | __RECOGNIZE__, ID = IFC_Pset_Caractéristiques, ID | Alignment | ExternalFace | Numérotation | Numéro niveau | Titre niveau | Longueur (cm) = NominalLength (cm) | IFC_Pset_Géométrie, Hauteur (cm) = IFC_Pset_Géométrie_P1 (POINT initial), Hauteur (cm) = IFC_Pset_Géométrie_P2 (POINT final), Hauteur (cm) = NominalHeight (cm) | IFC_Pset_Géométrie, Cote (cm) = IFC_Pset_Géométrie_P1 (POINT initial), Cote (cm) = IFC_Pset_Géométrie_P2 (POINT final), Cote (cm) = IFC_Pset_Système de Référence Altimétrique_INFÉRIEUR, delta (cm) = IFC_Pset_Système de Référence Altimétrique_INFÉRIEUR, delta (P1) (cm) = IFC_Pset_Système de Référence Altimétrique_INFÉRIEUR, delta (P2) (cm) | IFC_Pset_Géométrie_P1 (POINT initial), Angle XY (deg) | IFC_Pset_Géométrie_P2 (POINT final), Angle XY (deg) | IFC_Pset_Système de Référence Altimétrique_SUPÉRIEUR, NIVEAU | IFC_Pset_Système de Référence Altimétrique_SUPÉRIEUR, delta (cm) = IFC_Pset_Système de Référence Altimétrique_SUPÉRIEUR, delta (P1) (cm) = IFC_Pset_Système de Référence Altimétrique_SUPÉRIEUR, delta (P2) (cm) | IFC_Pset_Système de Référence Altimétrique_INFÉRIEUR, NIVEAU | Longueur Pied (cm) = Longueur Tête (cm) | Hauteur Maximale (cm) = Hauteur Minimale (cm) | Surface en Plan (cm2) = Surface Pied (cm2) = Surface Tête (cm2) | Surface de la Paroi (cm2) | Volume (cm3) | GrossVolume (cm3) | NetVolume (cm3) | GrossFootprintArea (cm2) = NetFootprintArea (cm2) | GrossSideArea (cm2) | NetSideArea (cm2)
Enveloppe 54383 | Rez-de-Jardin | 54383 | 0 | 1 | 0094 | 02 | Rez-de-Jardin | 150.166 | 291.413 | -1.94511e-11 | 0.264812 | 180.265 | HAUT Rez-de-Jardin (Rez-de-chaussée 1047) | 0.0128504 | Rez-de-Jardin (Rez-de-Jardin 15545) | 150.2 | 291.4 | 1200 | 43800 | 350000 | 328203 | 328203 | 1126.25 | 43760.5 | 43760.5
Enveloppe 54584 | Rez-de-Jardin | 54584 | 0 | 1 | 0095 | 02 | Rez-de-Jardin | 224.448 | 291.413 | -1.94511e-11 | 0.375234 | 180.375 | HAUT Rez-de-Jardin (Rez-de-chaussée 1047) | 0.0128504 | Rez-de-Jardin (Rez-de-Jardin 15545) | 224.4 | 291.4 | 1800 | 65400 | 520000 | 490553 | 490553 | 1683.36 | 65407.1 | 65407.1
Enveloppe 3464 | Rez-de-chaussée | 3464 | 0 | 0 | 0030 | 03 | Rez-de-chaussée | 44.2406 | 393.395 | 0.0128504 | 176.399 | 356.399 | HAUT Rez-de-chaussée (Niveau 1 2343) | -84.3871 | Rez-de-chaussée (Rez-de-chaussée 1047) | 44.2 | 393.4 | 400 | 17400 | 140000 | 130530 | 130530 | 331.804 | 17404 | 17404
Enveloppe 3269 | Rez-de-chaussée | 3269 | 1 | 0 | 0024 | 03 | Rez-de-chaussée | 538.048 | 393.395 | 0.0128504 | 0.083409 | 180.083 | HAUT Rez-de-chaussée (Niveau 1 2343) | -84.3871 | Rez-de-chaussée (Rez-de-chaussée 1047) | 538 | 393.4 | 4300 | 211600 | 1690000 | 1587492 | 1439014 | 4035.36 | 211666 | 191869

# IfcWallStandardCase: default 750, Enveloppe 53053
In: Rez-de-Jardin
Type - Material: <aucun> 75 cm
Description: Enveloppe; Group: ...de stratigraphies = default; ...de matériaux et couleurs = Ivoire clair; ...de matériaux et couleurs - 1 = Ivoire clair; ...de matériaux et couleurs - 2 = Ivoire clair
__RECOGNIZE__ - ID: 53053; TPLG: 366; TPLG_OD: 9000; GENERATE: 1
CTLG_EXTERNAL_LINK - 0, DocType: 2; 0, Tag: 0; 0, Crc: 1977773087; 1, DocType: 2; 1, Tag: 100; 1, Crc: 1977773087; 2, DocType: 2; 2, Tag: 200; 2, Crc: 1977773087; 3, DocType: 9; 3, Tag: 0; 3, Crc: 1567078605
IFC_PSET_PolygonOffset - polygonOffsetFactor: 2; polygonOffsetUnits: 2
IFC_Pset_Alignment - Alignment: 0
IFC_Pset_Strat_Detail_Align - ExternalFace: 0
IFC_Pset_Caractéristiques - ID: 53053; Numérotation: 0082; Numéro niveau: 02; Titre niveau: Rez-de-Jardin; Stratigraphie: default [750,00]; Épaisseur: 75 cm; Épaisseur VARIABLE: no
IFC_Pset_Caractéristiques_FRUIT - Fruit: no; Taille: 0 cm
IFC_Pset_Géométrie - Forme en Élévation: rectangle; Longueur: 40.5194 cm; Hauteur: 291.413 cm; Cote: -1.94511e-11 cm
IFC_Pset_Géométrie_P1 (POINT initial) - Hauteur: 291.413 cm; Cote: -1.94511e-11 cm; Angle XY: 90.2312 deg
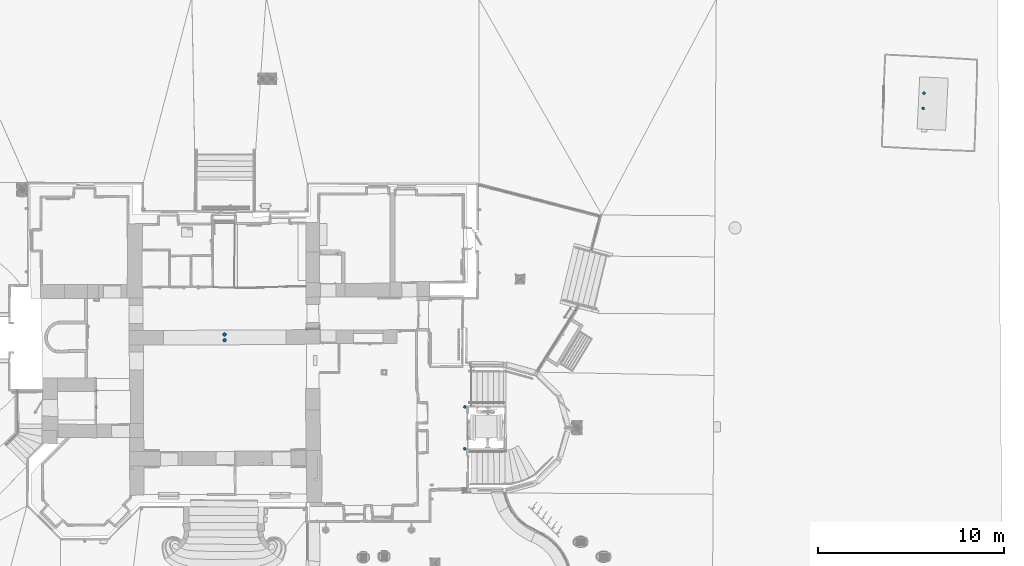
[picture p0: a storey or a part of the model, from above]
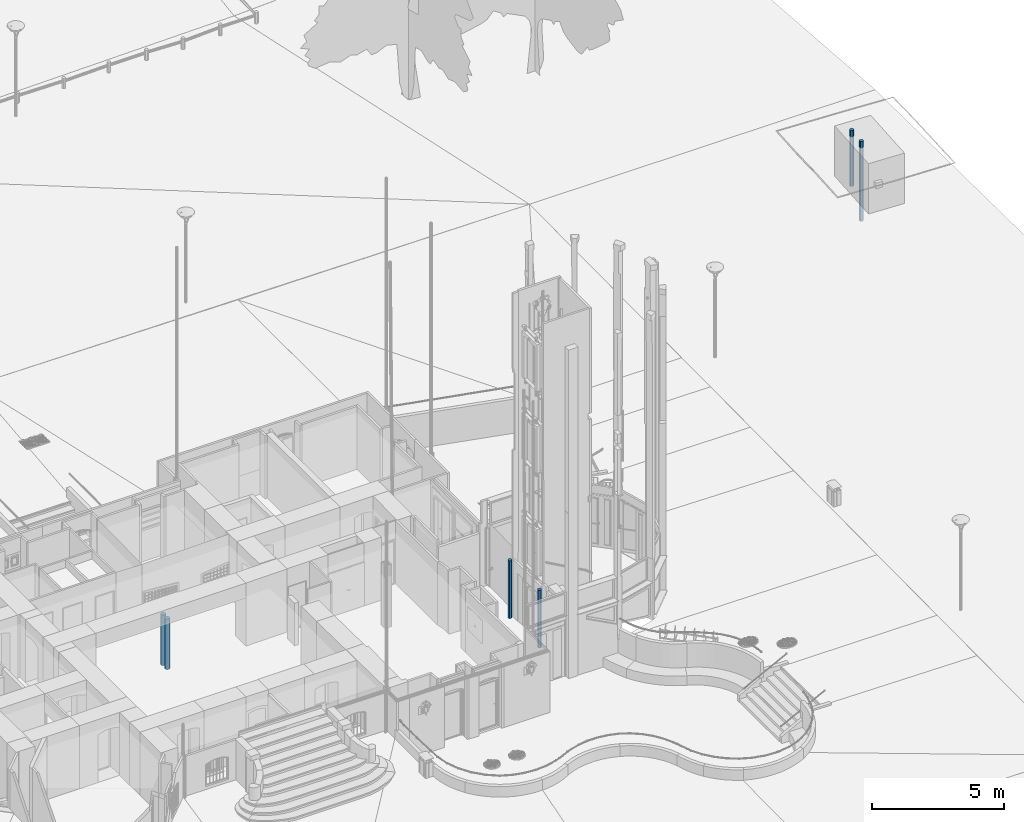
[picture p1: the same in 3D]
Properties of the parts of a building model (IFC2X3), part 28 of 37

# IfcWallStandardCase: default 750, Enveloppe 53053
IFC_Pset_Géométrie_P2 (POINT final) - Hauteur: 291.413 cm; Cote: -1.94511e-11 cm; Angle XY: 270.231 deg
IFC_Pset_Système de Référence Altimétrique_SUPÉRIEUR - NIVEAU: HAUT Rez-de-Jardin (Rez-de-chaussée 1047); delta: 0.0128504 cm; delta (P1): 0.0128504 cm; delta (P2): 0.0128504 cm; sous Niveau: <aucun>
IFC_Pset_Système de Référence Altimétrique_INFÉRIEUR - NIVEAU: Rez-de-Jardin (Rez-de-Jardin 15545); delta: -1.94511e-11 cm; delta (P1): -1.94511e-11 cm; delta (P2): -1.94511e-11 cm; sous Niveau: <aucun>
IFC_Pset_Données Métré - Longueur Pied: 40.5 cm; Longueur Tête: 40.5 cm; Hauteur Maximale: 291.4 cm; Hauteur Minimale: 291.4 cm; Surface en Plan: 3000 cm2; Surface Pied: 3000 cm2; Surface Tête: 3000 cm2; Surface de la Paroi: 11800 cm2; Volume: 890000 cm3
IFC_Pset_Matériaux - Face gauche: Ivoire clair; Face droite: Ivoire clair; Face latérale: Ivoire clair
Pset_WallCommon - Reference: default [750,00] (..\VERTICALES\Default\)
BaseQuantities - GrossVolume: 885592 cm3; NetVolume: 885592 cm3; NominalLength: 40.5194 cm; NominalWidth: 75 cm; NominalHeight: 291.413 cm; GrossFootprintArea: 3038.95 cm2; NetFootprintArea: 3038.95 cm2; GrossSideArea: 11807.9 cm2; NetSideArea: 11807.9 cm2

# IfcWallStandardCase: default 760 (4)
In: Rez-de-Jardin
Type - Material: <aucun> 76 cm
Description: Enveloppe; Group: ...de stratigraphies = default; ...de matériaux et couleurs = Ivoire clair; ...de matériaux et couleurs - 1 = Ivoire clair; ...de matériaux et couleurs - 2 = Ivoire clair
__RECOGNIZE__ - TPLG: 366; TPLG_OD: 9000; GENERATE: 1
CTLG_EXTERNAL_LINK - 0, DocType: 2; 0, Tag: 0; 0, Crc: 1977773087; 1, DocType: 2; 1, Tag: 100; 1, Crc: 1977773087; 2, DocType: 2; 2, Tag: 200; 2, Crc: 1977773087; 3, DocType: 9; 3, Tag: 0; 3, Crc: -1270741363
IFC_PSET_PolygonOffset - polygonOffsetFactor: 2; polygonOffsetUnits: 2
IFC_Pset_Caractéristiques - Numéro niveau: 02; Titre niveau: Rez-de-Jardin; Stratigraphie: default [760,00]; Épaisseur: 76 cm
IFC_Pset_Caractéristiques_FRUIT - Fruit: no; Taille: 0 cm
IFC_Pset_Géométrie - Forme en Élévation: rectangle; Hauteur: 291.413 cm; Cote: -1.94511e-11 cm
IFC_Pset_Géométrie_P1 (POINT initial) - Hauteur: 291.413 cm; Cote: -1.94511e-11 cm
IFC_Pset_Géométrie_P2 (POINT final) - Hauteur: 291.413 cm; Cote: -1.94511e-11 cm
IFC_Pset_Système de Référence Altimétrique_SUPÉRIEUR - NIVEAU: HAUT Rez-de-Jardin (Rez-de-chaussée 1047); delta: 0.0128504 cm; delta (P1): 0.0128504 cm; delta (P2): 0.0128504 cm; sous Niveau: <aucun>
IFC_Pset_Système de Référence Altimétrique_INFÉRIEUR - NIVEAU: Rez-de-Jardin (Rez-de-Jardin 15545); delta: -1.94511e-11 cm; delta (P1): -1.94511e-11 cm; delta (P2): -1.94511e-11 cm; sous Niveau: <aucun>
IFC_Pset_Données Métré - Hauteur Maximale: 291.4 cm; Hauteur Minimale: 291.4 cm
IFC_Pset_Matériaux - Face gauche: Ivoire clair; Face droite: Ivoire clair; Face latérale: Ivoire clair
Pset_WallCommon - Reference: default [760,00] (..\VERTICALES\Default\)
BaseQuantities - NominalHeight: 291.413 cm
Name | __RECOGNIZE__, ID = IFC_Pset_Caractéristiques, ID | Alignment | ExternalFace | Numérotation | Épaisseur VARIABLE | Longueur (cm) = NominalLength (cm) | IFC_Pset_Géométrie_P1 (POINT initial), Angle XY (deg) | IFC_Pset_Géométrie_P2 (POINT final), Angle XY (deg) | Longueur Pied (cm) = Longueur Tête (cm) | Surface en Plan (cm2) = Surface Pied (cm2) = Surface Tête (cm2) | Surface de la Paroi (cm2) | Volume (cm3) | GrossVolume (cm3) | NetVolume (cm3) | NominalWidth (cm) | GrossFootprintArea (cm2) = NetFootprintArea (cm2) | GrossSideArea (cm2) | NetSideArea (cm2)
Enveloppe 71762 | 71762 | 0 | 0 | 0152 | yes | 154.033 | 90.2312 | 270.231 | 154 | 11700 | 44900 | 3410000 | 3417456 | 3417456 | 76.1344 | 11727.2 | 44887.2 | 44887.2
Enveloppe 64663 | 64663 | 1 | 0 | 0115 | no | 196.241 | 90.2312 | 270.231 | 196.2 | 14900 | 57200 | 4350000 | 4346226 | 4346226 | 76 | 14914.3 | 57187.2 | 57187.2
Enveloppe 70947 | 70947 | 0 | 0 | 0144 | yes | 419.164 | 90.2312 | 270.231 | 419.1 | 32100 | 122100 | 9400000 | 9360888 | 7690916 | 76.6344 | 32122.4 | 122150 | 100438
Enveloppe 53322 | 53322 | 0 | 1 | 0089 | yes | 240.769 | 89.9398 | 269.94 | 240.7 | 18400 | 70100 | 5400000 | 5379166 | 3937628 | 76.6665 | 18458.9 | 70163.1 | 51319.5

# IfcWallStandardCase: default 77, Enveloppe courbe 170097
In: Niveau 2
Type - Material: <aucun> 7.7 cm
Description: Enveloppe courbe; Group: ...de matériaux et couleurs = Blanc; ...de matériaux et couleurs - 1 = Blanc; ...de matériaux et couleurs - 2 = Blanc; ...de stratigraphies = default
__RECOGNIZE__ - ID: 170097; TPLG: 367; TPLG_OD: 9001; GENERATE: 1
CTLG_EXTERNAL_LINK - 0, DocType: 2; 0, Tag: 0; 0, Crc: -746779066; 1, DocType: 2; 1, Tag: 100; 1, Crc: -746779066; 2, DocType: 2; 2, Tag: 200; 2, Crc: -746779066; 3, DocType: 9; 3, Tag: 0; 3, Crc: -193091668
IFC_PSET_PolygonOffset - polygonOffsetFactor: 2; polygonOffsetUnits: 2
IFC_Pset_Alignment - Alignment: 1
IFC_Pset_Strat_Detail_Align - ExternalFace: 0
IFC_Pset_Caractéristiques - ID: 170097; Numérotation: 12; Numéro niveau: 05; Titre niveau: Niveau 2; Stratigraphie: default [77,00]; Épaisseur: 7.7 cm; Épaisseur VARIABLE: no
IFC_Pset_Caractéristiques_FRUIT - Fruit: no; Taille: 0 cm
IFC_Pset_Géométrie_P1 (POINT initial) - Hauteur: 303.105 cm; Cote: 0 cm; Angle XY: 13.4122 deg
IFC_Pset_Géométrie_P2 (POINT final) - Hauteur: 303.105 cm; Cote: 0 cm; Angle XY: 193.412 deg
IFC_Pset_Géométrie - Rayon: 187.359 cm; Point arc: [-686,1; -217,3] cm; Centre: [-674,0; -34,2] cm; Angle de la Tangente: 4.50132 deg; Forme en Élévation: rectangle; Longueur: 43.8584 cm; Hauteur: 303.105 cm; Cote: 0 cm
IFC_Pset_Système de Référence Altimétrique_SUPÉRIEUR - NIVEAU: HAUT Mezzanine (Couverture 2134); delta: -211.598 cm; delta (P1): -211.598 cm; delta (P2): -211.598 cm; sous Niveau: <aucun>
IFC_Pset_Système de Référence Altimétrique_INFÉRIEUR - NIVEAU: Niveau 2 (Niveau 2 13545); delta: 0 cm; delta (P1): 0 cm; delta (P2): 0 cm; sous Niveau: <aucun>
IFC_Pset_Données Métré - Longueur Pied: 43.9 cm; Longueur Tête: 43.9 cm; Hauteur Maximale: 303.1 cm; Hauteur Minimale: 303.1 cm; Surface en Plan: 200 cm2; Surface Pied: 400 cm2; Surface Tête: 400 cm2; Surface de la Paroi: 13300 cm2; Volume: 110000 cm3
IFC_Pset_Matériaux - Face gauche: Blanc; Face droite: Blanc; Face latérale: Blanc
Pset_WallCommon - Reference: default [77,00] (..\VERTICALES\Default\)
BaseQuantities - GrossVolume: 102080 cm3; NetVolume: 102080 cm3; NominalLength: 43.8584 cm; NominalWidth: 7.67882 cm; NominalHeight: 303.105 cm; GrossFootprintArea: 336.781 cm2; NetFootprintArea: 336.781 cm2; GrossSideArea: 13293.7 cm2; NetSideArea: 13293.7 cm2

# IfcWallStandardCase: default 770 (7)
In: Rez-de-Jardin
Type - Material: <aucun> 77 cm
Description: Enveloppe; Group: ...de stratigraphies = default; ...de matériaux et couleurs = Ivoire clair; ...de matériaux et couleurs - 1 = Ivoire clair; ...de matériaux et couleurs - 2 = Ivoire clair
__RECOGNIZE__ - TPLG: 366; TPLG_OD: 9000; GENERATE: 1
CTLG_EXTERNAL_LINK - 0, DocType: 2; 0, Tag: 0; 0, Crc: 1977773087; 1, DocType: 2; 1, Tag: 100; 1, Crc: 1977773087; 2, DocType: 2; 2, Tag: 200; 2, Crc: 1977773087; 3, DocType: 9; 3, Tag: 0; 3, Crc: -787070505
IFC_PSET_PolygonOffset - polygonOffsetFactor: 2; polygonOffsetUnits: 2
IFC_Pset_Alignment - Alignment: 0
IFC_Pset_Caractéristiques - Numéro niveau: 02; Titre niveau: Rez-de-Jardin; Stratigraphie: default [770,00]; Épaisseur: 77 cm
IFC_Pset_Caractéristiques_FRUIT - Fruit: no; Taille: 0 cm
IFC_Pset_Géométrie - Forme en Élévation: rectangle; Hauteur: 291.413 cm; Cote: -1.94511e-11 cm
IFC_Pset_Géométrie_P1 (POINT initial) - Hauteur: 291.413 cm; Cote: -1.94511e-11 cm
IFC_Pset_Géométrie_P2 (POINT final) - Hauteur: 291.413 cm; Cote: -1.94511e-11 cm
IFC_Pset_Système de Référence Altimétrique_SUPÉRIEUR - NIVEAU: HAUT Rez-de-Jardin (Rez-de-chaussée 1047); delta: 0.0128504 cm; delta (P1): 0.0128504 cm; delta (P2): 0.0128504 cm; sous Niveau: <aucun>
IFC_Pset_Système de Référence Altimétrique_INFÉRIEUR - NIVEAU: Rez-de-Jardin (Rez-de-Jardin 15545); delta: -1.94511e-11 cm; delta (P1): -1.94511e-11 cm; delta (P2): -1.94511e-11 cm; sous Niveau: <aucun>
IFC_Pset_Données Métré - Hauteur Maximale: 291.4 cm; Hauteur Minimale: 291.4 cm
IFC_Pset_Matériaux - Face gauche: Ivoire clair; Face droite: Ivoire clair; Face latérale: Ivoire clair
Pset_WallCommon - Reference: default [770,00] (..\VERTICALES\Default\)
BaseQuantities - NominalHeight: 291.413 cm
Name | __RECOGNIZE__, ID = IFC_Pset_Caractéristiques, ID | ExternalFace | Numérotation | Épaisseur VARIABLE | Longueur (cm) = NominalLength (cm) | IFC_Pset_Géométrie_P1 (POINT initial), Angle XY (deg) | IFC_Pset_Géométrie_P2 (POINT final), Angle XY (deg) | Longueur Pied (cm) = Longueur Tête (cm) | Surface en Plan (cm2) = Surface Pied (cm2) = Surface Tête (cm2) | Surface de la Paroi (cm2) | Volume (cm3) | GrossVolume (cm3) | NetVolume (cm3) | NominalWidth (cm) | GrossFootprintArea (cm2) = NetFootprintArea (cm2) | GrossSideArea (cm2) | NetSideArea (cm2)
Enveloppe 72358 | 72358 | 0 | 0159 | no | 99.0413 | 179.302 | 359.302 | 99 | 7600 | 28800 | 2220000 | 2222371 | 536488 | 77 | 7626.18 | 28862 | 6967.37
Enveloppe 69960 | 69960 | 1 | 0133 | no | 236.858 | 90.1745 | 270.175 | 236.9 | 18200 | 69000 | 5310000 | 5314812 | 5314812 | 77 | 18238.1 | 69023.5 | 69023.5
Enveloppe 68570 | 68570 | 1 | 0130 | yes | 184.711 | 0.924713 | 180.925 | 184.7 | 14600 | 53800 | 4250000 | 4250266 | 2485976 | 78.9611 | 14585 | 53827.4 | 31242.7
Enveloppe 53161 | 53161 | 0 | 0086 | yes | 200.382 | 0.193362 | 180.193 | 200.4 | 15600 | 58400 | 4550000 | 4553963 | 4553963 | 77.9868 | 15627.2 | 58394 | 58394
Enveloppe 53189 | 53189 | 1 | 0087 | yes | 120.053 | 90.8577 | 270.858 | 120.1 | 9300 | 35000 | 2730000 | 2718478 | 2718478 | 77.704 | 9328.6 | 34985.1 | 34985.1
Enveloppe 53121 | 53121 | 0 | 0084 | no | 205.326 | 0.300243 | 180.3 | 205.3 | 15800 | 59800 | 4600000 | 4607279 | 2942642 | 77 | 15810.1 | 59834.8 | 38216.1
Enveloppe 53149 | 53149 | 0 | 0085 | no | 183.55 | 0.107277 | 180.107 | 183.6 | 14100 | 53500 | 4120000 | 4118651 | 4118651 | 77 | 14133.4 | 53489 | 53489

# IfcWallStandardCase: default 78 (2)
Type - Material: <aucun> 7.8 cm
__RECOGNIZE__ - GENERATE: 1
CTLG_EXTERNAL_LINK - 0, DocType: 2; 0, Tag: 0; 1, DocType: 2; 1, Tag: 100; 2, DocType: 2; 2, Tag: 200; 3, DocType: 9; 3, Tag: 0; 3, Crc: -508437552
IFC_PSET_PolygonOffset - polygonOffsetFactor: 2; polygonOffsetUnits: 2
IFC_Pset_Alignment - Alignment: 1
IFC_Pset_Strat_Detail_Align - ExternalFace: 0
IFC_Pset_Caractéristiques - Stratigraphie: default [78,00]; Épaisseur: 7.8 cm; Épaisseur VARIABLE: no
IFC_Pset_Caractéristiques_FRUIT - Fruit: no; Taille: 0 cm
IFC_Pset_Système de Référence Altimétrique_SUPÉRIEUR - sous Niveau: <aucun>
IFC_Pset_Système de Référence Altimétrique_INFÉRIEUR - sous Niveau: <aucun>
Pset_WallCommon - Reference: default [78,00] (..\VERTICALES\Default\)
Name | In | Description | __RECOGNIZE__, ID = IFC_Pset_Caractéristiques, ID | TPLG | TPLG_OD | 0, Crc = 1, Crc = 2, Crc | Numérotation | Numéro niveau | Titre niveau | Forme en Élévation | Longueur (cm) = NominalLength (cm) | IFC_Pset_Géométrie, Hauteur (cm) = IFC_Pset_Géométrie_P1 (POINT initial), Hauteur (cm) | IFC_Pset_Géométrie, Cote (cm) = IFC_Pset_Géométrie_P1 (POINT initial), Cote (cm) = IFC_Pset_Géométrie_P2 (POINT final), Cote (cm) = IFC_Pset_Système de Référence Altimétrique_INFÉRIEUR, delta (cm) = IFC_Pset_Système de Référence Altimétrique_INFÉRIEUR, delta (P1) (cm) = IFC_Pset_Système de Référence Altimétrique_INFÉRIEUR, delta (P2) (cm) | IFC_Pset_Géométrie_P1 (POINT initial), Angle XY (deg) | IFC_Pset_Géométrie_P2 (POINT final), Hauteur (cm) | IFC_Pset_Géométrie_P2 (POINT final), Angle XY (deg) | IFC_Pset_Système de Référence Altimétrique_SUPÉRIEUR, NIVEAU | IFC_Pset_Système de Référence Altimétrique_SUPÉRIEUR, delta (cm) = IFC_Pset_Système de Référence Altimétrique_SUPÉRIEUR, delta (P1) (cm) = IFC_Pset_Système de Référence Altimétrique_SUPÉRIEUR, delta (P2) (cm) | IFC_Pset_Système de Référence Altimétrique_INFÉRIEUR, NIVEAU | Longueur Pied (cm) | Longueur Tête (cm) | Hauteur Maximale (cm) | Hauteur Minimale (cm) | Surface en Plan (cm2) | Surface Pied (cm2) = Surface Tête (cm2) | Surface de la Paroi (cm2) | Volume (cm3) | Face gauche = Face droite = Face latérale | GrossVolume (cm3) | NetVolume (cm3) | NominalWidth (cm) | NominalHeight (cm) | GrossFootprintArea (cm2) = NetFootprintArea (cm2) | GrossSideArea (cm2) | NetSideArea (cm2) | Group
Enveloppe 65396 | Rez-de-Jardin | Enveloppe | 65396 | 366 | 9000 | 1977773087 | 0122 | 02 | Rez-de-Jardin | rectangle | 192.315 | 291.413 | -1.94511e-11 | 90.0023 | 291.413 | 270.002 | HAUT Rez-de-Jardin (Rez-de-chaussée 1047) | 0.0128504 | Rez-de-Jardin (Rez-de-Jardin 15545) | 192.3 | 192.3 | 291.4 | 291.4 | 1500 | 1500 | 56000 | 450000 | Ivoire clair | 437136 | 303475 | 7.8 | 291.413 | 1500.06 | 56043.1 | 38907.1 | ...de stratigraphies = default; ...de matériaux et couleurs = Ivoire clair; ...de matériaux et couleurs - 1 = Ivoire clair; ...de matériaux et couleurs - 2 = Ivoire clair
Enveloppe courbe 169375 | Niveau 2 | Enveloppe courbe | 169375 | 367 | 9001 | -746779066 | 08 | 05 | Niveau 2 | trapèze | 33.1177 | 354.708 | 0 | 11.7143 | 385.012 | 191.714 | HAUT Mezzanine (Couverture 2134) | 0 | Niveau 2 (Niveau 2 13545) | 33.1 | 44.9 | 385 | 354.7 | 200 | 300 | 12300 | 100000 | Blanc | 95356.8 | 95356.8 | 7.78493 | 369.86 | 257.819 | 12248.9 | 12248.9 | ...de matériaux et couleurs = Blanc; ...de matériaux et couleurs - 1 = Blanc; ...de matériaux et couleurs - 2 = Blanc; ...de stratigraphies = default | IFC_Pset_Géométrie - Rayon: 161.982 cm; Point arc: [-793,4; -150,3] cm; Centre: [-646,7; -91,3] cm; Angle de la Tangente: 3.62375 deg

# IfcWallStandardCase: default 790 (4)
In: Rez-de-Jardin
Type - Material: <aucun> 79 cm
Description: Enveloppe; Group: ...de stratigraphies = default; ...de matériaux et couleurs = Ivoire clair; ...de matériaux et couleurs - 1 = Ivoire clair; ...de matériaux et couleurs - 2 = Ivoire clair
__RECOGNIZE__ - TPLG: 366; TPLG_OD: 9000; GENERATE: 1
CTLG_EXTERNAL_LINK - 0, DocType: 2; 0, Tag: 0; 0, Crc: 1977773087; 1, DocType: 2; 1, Tag: 100; 1, Crc: 1977773087; 2, DocType: 2; 2, Tag: 200; 2, Crc: 1977773087; 3, DocType: 9; 3, Tag: 0; 3, Crc: -984971108
IFC_PSET_PolygonOffset - polygonOffsetFactor: 2; polygonOffsetUnits: 2
IFC_Pset_Caractéristiques - Numéro niveau: 02; Titre niveau: Rez-de-Jardin; Stratigraphie: default [790,00]; Épaisseur: 79 cm; Épaisseur VARIABLE: no
IFC_Pset_Caractéristiques_FRUIT - Fruit: no; Taille: 0 cm
IFC_Pset_Géométrie - Forme en Élévation: rectangle
IFC_Pset_Système de Référence Altimétrique_SUPÉRIEUR - NIVEAU: HAUT Rez-de-Jardin (Rez-de-chaussée 1047); delta: 0.0128504 cm; delta (P1): 0.0128504 cm; delta (P2): 0.0128504 cm; sous Niveau: <aucun>
IFC_Pset_Système de Référence Altimétrique_INFÉRIEUR - NIVEAU: Rez-de-Jardin (Rez-de-Jardin 15545); sous Niveau: <aucun>
IFC_Pset_Matériaux - Face gauche: Ivoire clair; Face droite: Ivoire clair; Face latérale: Ivoire clair
Pset_WallCommon - Reference: default [790,00] (..\VERTICALES\Default\)
BaseQuantities - NominalWidth: 79 cm
Name | __RECOGNIZE__, ID = IFC_Pset_Caractéristiques, ID | Alignment | ExternalFace | Numérotation | Longueur (cm) = NominalLength (cm) | IFC_Pset_Géométrie, Hauteur (cm) = IFC_Pset_Géométrie_P1 (POINT initial), Hauteur (cm) = IFC_Pset_Géométrie_P2 (POINT final), Hauteur (cm) = NominalHeight (cm) | IFC_Pset_Géométrie, Cote (cm) = IFC_Pset_Géométrie_P1 (POINT initial), Cote (cm) = IFC_Pset_Géométrie_P2 (POINT final), Cote (cm) = delta (cm) = delta (P1) (cm) = delta (P2) (cm) | IFC_Pset_Géométrie_P1 (POINT initial), Angle XY (deg) | IFC_Pset_Géométrie_P2 (POINT final), Angle XY (deg) | Longueur Pied (cm) = Longueur Tête (cm) | Hauteur Maximale (cm) = Hauteur Minimale (cm) | Surface en Plan (cm2) = Surface Pied (cm2) = Surface Tête (cm2) | Surface de la Paroi (cm2) | Volume (cm3) | GrossVolume (cm3) | NetVolume (cm3) | GrossFootprintArea (cm2) = NetFootprintArea (cm2) | GrossSideArea (cm2) | NetSideArea (cm2)
Enveloppe 73241 | 73241 | 0 | 1 | 0164 | 108.972 | 291.413 | -1.94511e-11 | 0.894188 | 180.894 | 109 | 291.4 | 8600 | 31800 | 2510000 | 2508708 | 2508708 | 8608.77 | 31755.8 | 31755.8
Enveloppe 53093 | 53093 | 0 | 0 | 0083 | 110.639 | 291.413 | -1.94511e-11 | 0.167059 | 180.167 | 110.6 | 291.4 | 8700 | 32200 | 2540000 | 2547089 | 2547089 | 8740.47 | 32241.6 | 32241.6
Enveloppe 56246 | 56246 | 1 | 1 | 0107 | 129.955 | 291.413 | -1.94511e-11 | 0.0303007 | 180.03 | 130 | 291.4 | 10300 | 37900 | 2990000 | 2991781 | 1530032 | 10266.5 | 37870.6 | 19367.5
Enveloppe 69980 | 69980 | 1 | 0 | 0134 | 658.24 | 67.8132 | 223.6 | 0.254341 | 180.254 | 658.3 | 67.8 | 52000 | 44600 | 3520000 | 3526353 | 3526353 | 52001 | 44637.4 | 44637.4

# IfcWallStandardCase: default 80 (14)
Type - Material: <aucun> 8 cm
Description: Enveloppe
__RECOGNIZE__ - TPLG: 366; TPLG_OD: 9000; GENERATE: 1
CTLG_EXTERNAL_LINK - 0, DocType: 2; 0, Tag: 0; 1, DocType: 2; 1, Tag: 100; 2, DocType: 2; 2, Tag: 200; 3, DocType: 9; 3, Tag: 0; 3, Crc: -1554559915
IFC_PSET_PolygonOffset - polygonOffsetFactor: 2; polygonOffsetUnits: 2
IFC_Pset_Caractéristiques - Stratigraphie: default [80,00]; Épaisseur: 8 cm; Épaisseur VARIABLE: no
IFC_Pset_Caractéristiques_FRUIT - Fruit: no; Taille: 0 cm
Pset_WallCommon - Reference: default [80,00] (..\VERTICALES\Default\)
BaseQuantities - NominalWidth: 8 cm
Name | In | __RECOGNIZE__, ID = IFC_Pset_Caractéristiques, ID | 0, Crc = 1, Crc = 2, Crc | Alignment | ExternalFace | Numérotation | Numéro niveau | Titre niveau | Forme en Élévation | Longueur (cm) = NominalLength (cm) | IFC_Pset_Géométrie, Hauteur (cm) = IFC_Pset_Géométrie_P1 (POINT initial), Hauteur (cm) | IFC_Pset_Géométrie, Cote (cm) = IFC_Pset_Géométrie_P1 (POINT initial), Cote (cm) = IFC_Pset_Géométrie_P2 (POINT final), Cote (cm) = IFC_Pset_Système de Référence Altimétrique_INFÉRIEUR, delta (cm) = IFC_Pset_Système de Référence Altimétrique_INFÉRIEUR, delta (P1) (cm) = IFC_Pset_Système de Référence Altimétrique_INFÉRIEUR, delta (P2) (cm) | IFC_Pset_Géométrie_P1 (POINT initial), Angle XY (deg) | IFC_Pset_Géométrie_P2 (POINT final), Hauteur (cm) | IFC_Pset_Géométrie_P2 (POINT final), Angle XY (deg) | IFC_Pset_Système de Référence Altimétrique_SUPÉRIEUR, NIVEAU | IFC_Pset_Système de Référence Altimétrique_SUPÉRIEUR, delta (cm) = IFC_Pset_Système de Référence Altimétrique_SUPÉRIEUR, delta (P1) (cm) = IFC_Pset_Système de Référence Altimétrique_SUPÉRIEUR, delta (P2) (cm) | IFC_Pset_Système de Référence Altimétrique_SUPÉRIEUR, sous Niveau | IFC_Pset_Système de Référence Altimétrique_INFÉRIEUR, NIVEAU | IFC_Pset_Système de Référence Altimétrique_INFÉRIEUR, sous Niveau | Longueur Pied (cm) | Longueur Tête (cm) | Hauteur Maximale (cm) | Hauteur Minimale (cm) | Surface en Plan (cm2) = Surface Pied (cm2) | Surface Tête (cm2) | Surface de la Paroi (cm2) | Volume (cm3) | Face gauche = Face droite = Face latérale | GrossVolume (cm3) | NetVolume (cm3) | NominalHeight (cm) | GrossFootprintArea (cm2) = NetFootprintArea (cm2) | GrossSideArea (cm2) | NetSideArea (cm2) | Group
Enveloppe 54675 | Rez-de-Jardin | 54675 | 1977773087 | 1 | 1 | 0097 | 02 | Rez-de-Jardin | rectangle | 410.663 | 291.413 | -1.94511e-11 | 0.342128 | 291.413 | 180.342 | HAUT Rez-de-Jardin (Rez-de-chaussée 1047) | 0.0128504 | <aucun> | Rez-de-Jardin (Rez-de-Jardin 15545) | <aucun> | 410.6 | 410.6 | 291.4 | 291.4 | 3300 | 3300 | 119600 | 960000 | Ivoire clair | 957380 | 508388 | 291.413 | 3285.3 | 119673 | 63548.6 | ...de stratigraphies = default; ...de matériaux et couleurs = Ivoire clair; ...de matériaux et couleurs - 1 = Ivoire clair; ...de matériaux et couleurs - 2 = Ivoire clair
Enveloppe 1703137 | Rez-de-chaussée | 1703137 | 1977773087 | 1 | 0 | 1171 | 03 | Rez-de-chaussée | rectangle | 27.1178 | 287.703 | 0.0128504 | 3.50335 | 287.703 | 183.503 | HAUT Rez-de-chaussée (Niveau 1 2343) | -293.795 | <aucun> | Rez-de-chaussée (Rez-de-chaussée 1047) | sous RDC | 27.1 | 27.1 | 287.7 | 287.7 | 200 | 200 | 7800 | 60000 | Ivoire clair | 62414.8 | 62414.8 | 287.703 | 216.942 | 7801.85 | 7801.85 | ...de stratigraphies = default; ...de matériaux et couleurs = Ivoire clair; ...de matériaux et couleurs - 1 = Ivoire clair; ...de matériaux et couleurs - 2 = Ivoire clair
Enveloppe 1703884 | Rez-de-chaussée | 1703884 | 1977773087 | 1 | 0 | 1172 | 03 | Rez-de-chaussée | rectangle | 159.551 | 287.703 | 0.0128504 | 90.2887 | 287.703 | 270.289 | HAUT Rez-de-chaussée (Niveau 1 2343) | -293.795 | <aucun> | Rez-de-chaussée (Rez-de-chaussée 1047) | sous RDC | 159.6 | 159.6 | 287.7 | 287.7 | 1300 | 1300 | 45900 | 370000 | Ivoire clair | 367227 | 27212.4 | 287.703 | 1276.41 | 45903.3 | 3401.55 | ...de stratigraphies = default; ...de matériaux et couleurs = Ivoire clair; ...de matériaux et couleurs - 1 = Ivoire clair; ...de matériaux et couleurs - 2 = Ivoire clair
Enveloppe 190281 | Niveau 2 | 190281 | 1977773087 | 1 | 0 | 0472 | 05 | Niveau 2 | rectangle | 89.1022 | 197 | 1.06581e-12 | 77.6196 | 197 | 257.62 | HAUT Niveau 2 (Mezzanine 49003) | -38 | <aucun> | Niveau 2 (Niveau 2 13545) | <aucun> | 89.1 | 89.1 | 197 | 197 | 700 | 700 | 17600 | 140000 | Ivoire clair | 140425 | 140425 | 197 | 712.818 | 17553.1 | 17553.1 | ...de stratigraphies = default; ...de matériaux et couleurs = Ivoire clair; ...de matériaux et couleurs - 1 = Ivoire clair; ...de matériaux et couleurs - 2 = Ivoire clair
Enveloppe 152386 | Niveau 2 | 152386 | 1977773087 | 0 | 0 | 0355 | 05 | Niveau 2 | rectangle | 180.42 | 240 | 1.42109e-12 | 90.7927 | 240 | 270.793 | HAUT Niveau 2 (Mezzanine 49003) | 5 | <aucun> | Niveau 2 (Niveau 2 13545) | <aucun> | 180.4 | 180.4 | 240 | 240 | 1400 | 1400 | 43300 | 350000 | Ivoire clair | 346406 | 65781.3 | 240 | 1443.36 | 43300.8 | 8222.67 | ...de stratigraphies = default; ...de matériaux et couleurs = Ivoire clair; ...de matériaux et couleurs - 1 = Ivoire clair; ...de matériaux et couleurs - 2 = Ivoire clair
Enveloppe 170245 | Niveau 2 | 170245 | 1977773087 | 0 | 0 | 0420 | 05 | Niveau 2 | rectangle | 188.91 | 235 | 1.42109e-12 | 0.309058 | 235 | 180.309 | HAUT Niveau 2 (Mezzanine 49003) | 1.42109e-12 | <aucun> | Niveau 2 (Niveau 2 13545) | <aucun> | 188.9 | 188.9 | 235 | 235 | 1500 | 1500 | 44400 | 360000 | Ivoire clair | 355151 | 287816 | 235 | 1511.28 | 44393.9 | 35977 | ...de stratigraphies = default; ...de matériaux et couleurs = Ivoire clair; ...de matériaux et couleurs - 1 = Ivoire clair; ...de matériaux et couleurs - 2 = Ivoire clair
Enveloppe 170226 | Niveau 2 | 170226 | 1977773087 | 0 | 0 | 0418 | 05 | Niveau 2 | rectangle | 87.4411 | 235 | 1.42109e-12 | 90.8556 | 235 | 270.856 | HAUT Niveau 2 (Mezzanine 49003) | 1.42109e-12 | <aucun> | Niveau 2 (Niveau 2 13545) | <aucun> | 87.4 | 87.4 | 235 | 235 | 700 | 700 | 20500 | 160000 | Ivoire clair | 164389 | 164389 | 235 | 699.529 | 20548.7 | 20548.7 | ...de stratigraphies = default; ...de matériaux et couleurs = Ivoire clair; ...de matériaux et couleurs - 1 = Ivoire clair; ...de matériaux et couleurs - 2 = Ivoire clair
Enveloppe 168225 | Niveau 2 | 168225 | 1977773087 | 0 | 0 | 0415 | 05 | Niveau 2 | rectangle | 104.011 | 218.5 | 1.42109e-12 | 89.8061 | 218.5 | 269.806 | HAUT Niveau 2 (Mezzanine 49003) | -16.5 | <aucun> | Niveau 2 (Niveau 2 13545) | <aucun> | 104 | 104 | 218.5 | 218.5 | 800 | 800 | 22700 | 180000 | Ivoire clair | 181811 | 181811 | 218.5 | 832.085 | 22726.3 | 22726.3 | ...de stratigraphies = default; ...de matériaux et couleurs = Ivoire clair; ...de matériaux et couleurs - 1 = Ivoire clair; ...de matériaux et couleurs - 2 = Ivoire clair
Enveloppe 172745 | Niveau 2 | 172745 | 1977773087 | 1 | 0 | 0439 | 05 | Niveau 2 | rectangle | 111.416 | 228 | 1.42109e-12 | 0.139796 | 228 | 180.14 | HAUT Niveau 2 (Mezzanine 49003) | -7 | <aucun> | Niveau 2 (Niveau 2 13545) | <aucun> | 111.4 | 111.4 | 228 | 228 | 900 | 900 | 25400 | 200000 | Ivoire clair | 203222 | 67727 | 228 | 891.325 | 25402.8 | 8465.88 | ...de stratigraphies = default; ...de matériaux et couleurs = Ivoire clair; ...de matériaux et couleurs - 1 = Ivoire clair; ...de matériaux et couleurs - 2 = Ivoire clair
Enveloppe 170861 | Niveau 2 | 170861 | 1977773087 | 1 | 0 | 0427 | 05 | Niveau 2 | rectangle | 103.465 | 208 | 1.42109e-12 | 90.6598 | 208 | 270.66 | HAUT Niveau 2 (Mezzanine 49003) | -27 | <aucun> | Niveau 2 (Niveau 2 13545) | <aucun> | 103.5 | 103.5 | 208 | 208 | 800 | 800 | 21500 | 170000 | Ivoire clair | 172165 | 46524.1 | 208 | 827.716 | 21520.6 | 5815.52 | ...de stratigraphies = default; ...de matériaux et couleurs = Ivoire clair; ...de matériaux et couleurs - 1 = Ivoire clair; ...de matériaux et couleurs - 2 = Ivoire clair
Enveloppe 161634 | Niveau 2 | 161634 | 1977773087 | 1 | 0 | 0386 | 05 | Niveau 2 | rectangle | 39.373 | 261.846 | 1.42109e-12 | 45.6567 | 261.846 | 225.657 | HAUT Niveau 2 (Mezzanine 49003) | 26.8456 | <aucun> | Niveau 2 (Niveau 2 13545) | <aucun> | 39.4 | 39.4 | 261.8 | 261.8 | 300 | 300 | 10300 | 80000 | Ivoire clair | 82477.2 | 82477.2 | 261.846 | 314.984 | 10309.7 | 10309.7 | ...de stratigraphies = default; ...de matériaux et couleurs = Ivoire clair; ...de matériaux et couleurs - 1 = Ivoire clair; ...de matériaux et couleurs - 2 = Ivoire clair
Enveloppe 159305 | Niveau 2 | 159305 | 1977773087 | 1 | 0 | 0376 | 05 | Niveau 2 | rectangle | 108.661 | 225 | 1.42109e-12 | 135.521 | 225 | 315.521 | HAUT Niveau 2 (Mezzanine 49003) | -10 | <aucun> | Niveau 2 (Niveau 2 13545) | <aucun> | 108.7 | 108.7 | 225 | 225 | 900 | 900 | 24500 | 200000 | Ivoire clair | 195589 | 68134.2 | 225 | 869.286 | 24448.7 | 8516.78 | ...de stratigraphies = default; ...de matériaux et couleurs = Ivoire clair; ...de matériaux et couleurs - 1 = Ivoire clair; ...de matériaux et couleurs - 2 = Ivoire clair
Enveloppe 168123 | Niveau 2 | 168123 | 1977773087 | 0 | 0 | 0414 | 05 | Niveau 2 | rectangle | 143.863 | 247.5 | 1.42109e-12 | 0.85764 | 247.5 | 180.858 | HAUT Niveau 2 (Mezzanine 49003) | 12.5 | <aucun> | Niveau 2 (Niveau 2 13545) | <aucun> | 143.9 | 143.9 | 247.5 | 247.5 | 1100 | 1100 | 35600 | 280000 | Ivoire clair | 284849 | 133735 | 247.5 | 1150.91 | 35606.2 | 16716.8 | ...de stratigraphies = default; ...de matériaux et couleurs = Ivoire clair; ...de matériaux et couleurs - 1 = Ivoire clair; ...de matériaux et couleurs - 2 = Ivoire clair
Enveloppe 194677 | Mezzanine | 194677 | -1156274542 | 0 | 1 | 0483 | 06 | Mezzanine | trapèze | 159.361 | 191.697 | 3.73035e-12 | 0.0515293 | 111.144 | 180.052 | Couverture (Couverture 2134) | 0 | Toit795368 | Mezzanine (Mezzanine 49003) | <aucun> | 159.4 | 178.6 | 191.7 | 111.1 | 1300 | 1400 | 24100 | 190000 | Chêne | 193044 | 193044 | 151.42 | 1274.89 | 24130.5 | 24130.5 | ...de matériaux et couleurs = Chêne; ...de stratigraphies = default; ...de matériaux et couleurs - 1 = Chêne; ...de matériaux et couleurs - 2 = Chêne

# IfcWallStandardCase: default 800 (2)
In: Rez-de-Jardin
Type - Material: <aucun> 80 cm
Description: Enveloppe; Group: ...de stratigraphies = default; ...de matériaux et couleurs = Ivoire clair; ...de matériaux et couleurs - 1 = Ivoire clair; ...de matériaux et couleurs - 2 = Ivoire clair
__RECOGNIZE__ - TPLG: 366; TPLG_OD: 9000; GENERATE: 1
CTLG_EXTERNAL_LINK - 0, DocType: 2; 0, Tag: 0; 0, Crc: 1977773087; 1, DocType: 2; 1, Tag: 100; 1, Crc: 1977773087; 2, DocType: 2; 2, Tag: 200; 2, Crc: 1977773087; 3, DocType: 9; 3, Tag: 0; 3, Crc: 2082775665
IFC_PSET_PolygonOffset - polygonOffsetFactor: 2; polygonOffsetUnits: 2
IFC_Pset_Alignment - Alignment: 1
IFC_Pset_Strat_Detail_Align - ExternalFace: 1
IFC_Pset_Caractéristiques - Numéro niveau: 02; Titre niveau: Rez-de-Jardin; Stratigraphie: default [800,00]; Épaisseur: 80 cm
IFC_Pset_Caractéristiques_FRUIT - Fruit: no; Taille: 0 cm
IFC_Pset_Géométrie - Forme en Élévation: rectangle; Hauteur: 291.413 cm; Cote: -1.94511e-11 cm
IFC_Pset_Géométrie_P1 (POINT initial) - Hauteur: 291.413 cm; Cote: -1.94511e-11 cm; Angle XY: 89.7948 deg
IFC_Pset_Géométrie_P2 (POINT final) - Hauteur: 291.413 cm; Cote: -1.94511e-11 cm; Angle XY: 269.795 deg
IFC_Pset_Système de Référence Altimétrique_SUPÉRIEUR - NIVEAU: HAUT Rez-de-Jardin (Rez-de-chaussée 1047); delta: 0.0128504 cm; delta (P1): 0.0128504 cm; delta (P2): 0.0128504 cm; sous Niveau: <aucun>
IFC_Pset_Système de Référence Altimétrique_INFÉRIEUR - NIVEAU: Rez-de-Jardin (Rez-de-Jardin 15545); delta: -1.94511e-11 cm; delta (P1): -1.94511e-11 cm; delta (P2): -1.94511e-11 cm; sous Niveau: <aucun>
IFC_Pset_Données Métré - Hauteur Maximale: 291.4 cm; Hauteur Minimale: 291.4 cm
IFC_Pset_Matériaux - Face gauche: Ivoire clair; Face droite: Ivoire clair; Face latérale: Ivoire clair
Pset_WallCommon - Reference: default [800,00] (..\VERTICALES\Default\)
BaseQuantities - NominalHeight: 291.413 cm
Name | __RECOGNIZE__, ID = IFC_Pset_Caractéristiques, ID | Numérotation | Épaisseur VARIABLE | Longueur (cm) = NominalLength (cm) | Longueur Pied (cm) = Longueur Tête (cm) | Surface en Plan (cm2) = Surface Pied (cm2) = Surface Tête (cm2) | Surface de la Paroi (cm2) | Volume (cm3) | GrossVolume (cm3) = NetVolume (cm3) | NominalWidth (cm) | GrossFootprintArea (cm2) = NetFootprintArea (cm2) | GrossSideArea (cm2) = NetSideArea (cm2)
Enveloppe 68454 | 68454 | 0128 | no | 20.5687 | 20.6 | 1600 | 6000 | 480000 | 479519 | 80 | 1645.49 | 5993.99
Enveloppe 68533 | 68533 | 0129 | yes | 257.752 | 257.8 | 21200 | 75100 | 6080000 | 6162647 | 82.0457 | 21147.5 | 75112.3

# IfcWallStandardCase: default 807, Enveloppe 72492
In: Rez-de-Jardin
Type - Material: <aucun> 80.7 cm
Description: Enveloppe; Group: ...de stratigraphies = default; ...de matériaux et couleurs = Ivoire clair; ...de matériaux et couleurs - 1 = Ivoire clair; ...de matériaux et couleurs - 2 = Ivoire clair
__RECOGNIZE__ - ID: 72492; TPLG: 366; TPLG_OD: 9000; GENERATE: 1
CTLG_EXTERNAL_LINK - 0, DocType: 2; 0, Tag: 0; 0, Crc: 1977773087; 1, DocType: 2; 1, Tag: 100; 1, Crc: 1977773087; 2, DocType: 2; 2, Tag: 200; 2, Crc: 1977773087; 3, DocType: 9; 3, Tag: 0; 3, Crc: -653589010
IFC_PSET_PolygonOffset - polygonOffsetFactor: 2; polygonOffsetUnits: 2
IFC_Pset_Alignment - Alignment: 1
IFC_Pset_Strat_Detail_Align - ExternalFace: 1
IFC_Pset_Caractéristiques - ID: 72492; Numérotation: 0161; Numéro niveau: 02; Titre niveau: Rez-de-Jardin; Stratigraphie: default [807,00]; Épaisseur: 80.7 cm; Épaisseur VARIABLE: no
IFC_Pset_Caractéristiques_FRUIT - Fruit: no; Taille: 0 cm
IFC_Pset_Géométrie - Forme en Élévation: rectangle; Longueur: 179.169 cm; Hauteur: 291.413 cm; Cote: -1.94511e-11 cm
IFC_Pset_Géométrie_P1 (POINT initial) - Hauteur: 291.413 cm; Cote: -1.94511e-11 cm; Angle XY: 0.483804 deg
IFC_Pset_Géométrie_P2 (POINT final) - Hauteur: 291.413 cm; Cote: -1.94511e-11 cm; Angle XY: 180.484 deg
IFC_Pset_Système de Référence Altimétrique_SUPÉRIEUR - NIVEAU: HAUT Rez-de-Jardin (Rez-de-chaussée 1047); delta: 0.0128504 cm; delta (P1): 0.0128504 cm; delta (P2): 0.0128504 cm; sous Niveau: <aucun>
IFC_Pset_Système de Référence Altimétrique_INFÉRIEUR - NIVEAU: Rez-de-Jardin (Rez-de-Jardin 15545); delta: -1.94511e-11 cm; delta (P1): -1.94511e-11 cm; delta (P2): -1.94511e-11 cm; sous Niveau: <aucun>
IFC_Pset_Données Métré - Longueur Pied: 179.2 cm; Longueur Tête: 179.2 cm; Hauteur Maximale: 291.4 cm; Hauteur Minimale: 291.4 cm; Surface en Plan: 14500 cm2; Surface Pied: 14500 cm2; Surface Tête: 14500 cm2; Surface de la Paroi: 52200 cm2; Volume: 4230000 cm3
IFC_Pset_Matériaux - Face gauche: Ivoire clair; Face droite: Ivoire clair; Face latérale: Ivoire clair
Pset_WallCommon - Reference: default [807,00] (..\VERTICALES\Default\)
BaseQuantities - GrossVolume: 4213515 cm3; NetVolume: 2750397 cm3; NominalLength: 179.169 cm; NominalWidth: 80.7 cm; NominalHeight: 291.413 cm; GrossFootprintArea: 14458.9 cm2; NetFootprintArea: 14458.9 cm2; GrossSideArea: 52212.1 cm2; NetSideArea: 34081.7 cm2

# IfcWallStandardCase: default 810 (2)
In: Rez-de-Jardin
Type - Material: <aucun> 81 cm
Description: Enveloppe
__RECOGNIZE__ - TPLG: 366; TPLG_OD: 9000; GENERATE: 1
CTLG_EXTERNAL_LINK - 0, DocType: 2; 0, Tag: 0; 1, DocType: 2; 1, Tag: 100; 2, DocType: 2; 2, Tag: 200; 3, DocType: 9; 3, Tag: 0; 3, Crc: -1819127894
IFC_PSET_PolygonOffset - polygonOffsetFactor: 2; polygonOffsetUnits: 2
IFC_Pset_Alignment - Alignment: 0
IFC_Pset_Caractéristiques - Numéro niveau: 02; Titre niveau: Rez-de-Jardin; Stratigraphie: default [810,00]; Épaisseur: 81 cm; Épaisseur VARIABLE: yes
IFC_Pset_Caractéristiques_FRUIT - Fruit: no; Taille: 0 cm
IFC_Pset_Géométrie - Forme en Élévation: rectangle; Hauteur: 291.413 cm; Cote: -1.94511e-11 cm
IFC_Pset_Géométrie_P1 (POINT initial) - Hauteur: 291.413 cm; Cote: -1.94511e-11 cm
IFC_Pset_Géométrie_P2 (POINT final) - Hauteur: 291.413 cm; Cote: -1.94511e-11 cm
IFC_Pset_Système de Référence Altimétrique_SUPÉRIEUR - NIVEAU: HAUT Rez-de-Jardin (Rez-de-chaussée 1047); delta: 0.0128504 cm; delta (P1): 0.0128504 cm; delta (P2): 0.0128504 cm; sous Niveau: <aucun>
IFC_Pset_Système de Référence Altimétrique_INFÉRIEUR - NIVEAU: Rez-de-Jardin (Rez-de-Jardin 15545); delta: -1.94511e-11 cm; delta (P1): -1.94511e-11 cm; delta (P2): -1.94511e-11 cm; sous Niveau: <aucun>
IFC_Pset_Données Métré - Hauteur Maximale: 291.4 cm; Hauteur Minimale: 291.4 cm
Pset_WallCommon - Reference: default [810,00] (..\VERTICALES\Default\)
BaseQuantities - NominalHeight: 291.413 cm
Name | __RECOGNIZE__, ID = IFC_Pset_Caractéristiques, ID | 0, Crc = 1, Crc = 2, Crc | ExternalFace | Numérotation | Longueur (cm) = NominalLength (cm) | IFC_Pset_Géométrie_P1 (POINT initial), Angle XY (deg) | IFC_Pset_Géométrie_P2 (POINT final), Angle XY (deg) | Longueur Pied (cm) = Longueur Tête (cm) | Surface en Plan (cm2) = Surface Pied (cm2) = Surface Tête (cm2) | Surface de la Paroi (cm2) | Volume (cm3) | Face gauche = Face droite = Face latérale | GrossVolume (cm3) | NetVolume (cm3) | NominalWidth (cm) | GrossFootprintArea (cm2) = NetFootprintArea (cm2) | GrossSideArea (cm2) | NetSideArea (cm2) | Group
Enveloppe 64975 | 64975 | 1552655706 | 1 | 0118 | 210.81 | 89.4074 | 269.407 | 210.8 | 17700 | 61400 | 5160000 | 18 Travertin romain | 5168501 | 3270226 | 84.1327 | 17736 | 61432.7 | 38752.7 | ...de stratigraphies = default; ...de matériaux et couleurs = 18 Travertin romain; ...de matériaux et couleurs - 1 = 18 Travertin romain; ...de matériaux et couleurs - 2 = 18 Travertin romain
Enveloppe 53024 | 53024 | 1977773087 | 0 | 0081 | 318.088 | 89.7628 | 269.763 | 318.1 | 26300 | 92700 | 7690000 | Ivoire clair | 7664204 | 7664204 | 82.6818 | 26300.1 | 92695.1 | 92695.1 | ...de stratigraphies = default; ...de matériaux et couleurs = Ivoire clair; ...de matériaux et couleurs - 1 = Ivoire clair; ...de matériaux et couleurs - 2 = Ivoire clair

# IfcWallStandardCase: default 82 (2)
In: Niveau 2
Type - Material: <aucun> 8.2 cm
Description: Enveloppe courbe; Group: ...de matériaux et couleurs = Blanc; ...de matériaux et couleurs - 1 = Blanc; ...de matériaux et couleurs - 2 = Blanc; ...de stratigraphies = default
__RECOGNIZE__ - TPLG: 367; TPLG_OD: 9001; GENERATE: 1
CTLG_EXTERNAL_LINK - 0, DocType: 2; 0, Tag: 0; 0, Crc: -746779066; 1, DocType: 2; 1, Tag: 100; 1, Crc: -746779066; 2, DocType: 2; 2, Tag: 200; 2, Crc: -746779066; 3, DocType: 9; 3, Tag: 0; 3, Crc: 2049263088
IFC_PSET_PolygonOffset - polygonOffsetFactor: 2; polygonOffsetUnits: 2
IFC_Pset_Alignment - Alignment: 1
IFC_Pset_Strat_Detail_Align - ExternalFace: 0
IFC_Pset_Caractéristiques - Numéro niveau: 05; Titre niveau: Niveau 2; Stratigraphie: default [82,00]; Épaisseur: 8.2 cm; Épaisseur VARIABLE: no
IFC_Pset_Caractéristiques_FRUIT - Fruit: no; Taille: 0 cm
IFC_Pset_Géométrie_P1 (POINT initial) - Cote: 0 cm
IFC_Pset_Géométrie_P2 (POINT final) - Cote: 0 cm
IFC_Pset_Géométrie - Forme en Élévation: trapèze; Cote: 0 cm
IFC_Pset_Système de Référence Altimétrique_SUPÉRIEUR - NIVEAU: HAUT Mezzanine (Couverture 2134); delta: 0 cm; delta (P1): 0 cm; delta (P2): 0 cm; sous Niveau: <aucun>
IFC_Pset_Système de Référence Altimétrique_INFÉRIEUR - NIVEAU: Niveau 2 (Niveau 2 13545); delta: 0 cm; delta (P1): 0 cm; delta (P2): 0 cm; sous Niveau: <aucun>
IFC_Pset_Données Métré - Surface en Plan: 200 cm2; Surface Pied: 300 cm2; Surface Tête: 300 cm2; Volume: 90000 cm3
IFC_Pset_Matériaux - Face gauche: Blanc; Face droite: Blanc; Face latérale: Blanc
Pset_WallCommon - Reference: default [82,00] (..\VERTICALES\Default\)
Name | __RECOGNIZE__, ID = IFC_Pset_Caractéristiques, ID | Numérotation | IFC_Pset_Géométrie_P1 (POINT initial), Hauteur (cm) = IFC_Pset_Géométrie, Hauteur (cm) | IFC_Pset_Géométrie_P1 (POINT initial), Angle XY (deg) | IFC_Pset_Géométrie_P2 (POINT final), Hauteur (cm) | IFC_Pset_Géométrie_P2 (POINT final), Angle XY (deg) | Rayon (cm) | Point arc | Centre | Angle de la Tangente (deg) | Longueur (cm) = NominalLength (cm) | Longueur Pied (cm) | Longueur Tête (cm) | Hauteur Maximale (cm) | Hauteur Minimale (cm) | Surface de la Paroi (cm2) | GrossVolume (cm3) = NetVolume (cm3) | NominalWidth (cm) | NominalHeight (cm) | GrossFootprintArea (cm2) = NetFootprintArea (cm2) | GrossSideArea (cm2) = NetSideArea (cm2)
Enveloppe courbe 169829 | 169829 | 09 | 331.608 | 11.7158 | 354.708 | 191.716 | 165.469 | [-776,3; -178,0] cm | [-655,2; -71,3] cm | 3.51006 | 33.8349 | 33.8 | 41 | 354.7 | 331.6 | 11600 | 94902.8 | 8.17372 | 343.158 | 276.557 | 11610.7
Enveloppe courbe 169856 | 169856 | 10 | 314.4 | 17.2883 | 332.548 | 197.288 | 113.347 | [-751,1; -198,9] cm | [-697,7; -103,6] cm | 6.29636 | 34.201 | 34.2 | 38.7 | 332.5 | 314.4 | 11100 | 90366 | 8.1682 | 323.474 | 279.361 | 11063.1

# IfcWallStandardCase: default 85 (15)
In: Niveau 2
Type - Material: <aucun> 8.5 cm
Description: Enveloppe; Group: ...de stratigraphies = default; ...de matériaux et couleurs = Ivoire clair; ...de matériaux et couleurs - 1 = Ivoire clair; ...de matériaux et couleurs - 2 = Ivoire clair
__RECOGNIZE__ - TPLG: 366; TPLG_OD: 9000; GENERATE: 1
CTLG_EXTERNAL_LINK - 0, DocType: 2; 0, Tag: 0; 0, Crc: 1977773087; 1, DocType: 2; 1, Tag: 100; 1, Crc: 1977773087; 2, DocType: 2; 2, Tag: 200; 2, Crc: 1977773087; 3, DocType: 9; 3, Tag: 0; 3, Crc: -986503532
IFC_PSET_PolygonOffset - polygonOffsetFactor: 2; polygonOffsetUnits: 2
IFC_Pset_Strat_Detail_Align - ExternalFace: 0
IFC_Pset_Caractéristiques - Numéro niveau: 05; Titre niveau: Niveau 2; Stratigraphie: default [85,00]; Épaisseur: 8.5 cm; Épaisseur VARIABLE: no
IFC_Pset_Caractéristiques_FRUIT - Fruit: no; Taille: 0 cm
IFC_Pset_Géométrie - Forme en Élévation: rectangle; Cote: 1.42109e-12 cm
IFC_Pset_Géométrie_P1 (POINT initial) - Cote: 1.42109e-12 cm
IFC_Pset_Géométrie_P2 (POINT final) - Cote: 1.42109e-12 cm
IFC_Pset_Système de Référence Altimétrique_SUPÉRIEUR - NIVEAU: HAUT Niveau 2 (Mezzanine 49003); sous Niveau: <aucun>
IFC_Pset_Système de Référence Altimétrique_INFÉRIEUR - NIVEAU: Niveau 2 (Niveau 2 13545); delta: 1.42109e-12 cm; delta (P1): 1.42109e-12 cm; delta (P2): 1.42109e-12 cm; sous Niveau: <aucun>
IFC_Pset_Matériaux - Face gauche: Ivoire clair; Face droite: Ivoire clair; Face latérale: Ivoire clair
Pset_WallCommon - Reference: default [85,00] (..\VERTICALES\Default\)
BaseQuantities - NominalWidth: 8.5 cm
Name | __RECOGNIZE__, ID = IFC_Pset_Caractéristiques, ID | Alignment | Numérotation | Longueur (cm) = NominalLength (cm) | IFC_Pset_Géométrie, Hauteur (cm) = IFC_Pset_Géométrie_P1 (POINT initial), Hauteur (cm) = IFC_Pset_Géométrie_P2 (POINT final), Hauteur (cm) = NominalHeight (cm) | IFC_Pset_Géométrie_P1 (POINT initial), Angle XY (deg) | IFC_Pset_Géométrie_P2 (POINT final), Angle XY (deg) | delta (cm) = delta (P1) (cm) = delta (P2) (cm) | Longueur Pied (cm) = Longueur Tête (cm) | Hauteur Maximale (cm) = Hauteur Minimale (cm) | Surface en Plan (cm2) = Surface Pied (cm2) = Surface Tête (cm2) | Surface de la Paroi (cm2) | Volume (cm3) | GrossVolume (cm3) | NetVolume (cm3) | GrossFootprintArea (cm2) = NetFootprintArea (cm2) | GrossSideArea (cm2) | NetSideArea (cm2)
Enveloppe 167087 | 167087 | 1 | 0409 | 103.409 | 235 | 0.1193 | 180.119 | 1.42109e-12 | 103.4 | 235 | 900 | 24300 | 220000 | 206560 | 206560 | 878.978 | 24301.2 | 24301.2
Enveloppe 161839 | 161839 | 1 | 0387 | 32.9403 | 235 | 138.542 | 318.542 | 0 | 32.9 | 235 | 300 | 7700 | 70000 | 65798.2 | 65798.2 | 279.992 | 7740.96 | 7740.96
Enveloppe 161633 | 161633 | 1 | 0385 | 114.163 | 223.704 | 45.6567 | 225.657 | -11.2965 | 114.2 | 223.7 | 1000 | 25500 | 230000 | 217079 | 84878.8 | 970.388 | 25538.7 | 9985.74
Enveloppe 166655 | 166655 | 1 | 0400 | 72.3312 | 230 | 179.112 | 359.112 | -5 | 72.3 | 230 | 700 | 16600 | 150000 | 141407 | 39412.4 | 614.815 | 16636.2 | 4636.75
Enveloppe 166680 | 166680 | 1 | 0401 | 152.666 | 235 | 0.532146 | 180.532 | 1.42109e-12 | 152.7 | 235 | 1400 | 35900 | 320000 | 304950 | 304950 | 1297.66 | 35876.5 | 35876.5
Enveloppe 166814 | 166814 | 0 | 0405 | 116.62 | 169 | 179.791 | 359.791 | -66 | 116.6 | 169 | 1000 | 19700 | 180000 | 167524 | 92881.8 | 991.268 | 19708.7 | 10927.3
Enveloppe 166903 | 166903 | 1 | 0406 | 37.8372 | 235 | 90.7179 | 270.718 | 1.42109e-12 | 37.8 | 235 | 300 | 8900 | 80000 | 75579.8 | 75579.8 | 321.616 | 8891.74 | 8891.74
Enveloppe 166745 | 166745 | 1 | 0403 | 32.8138 | 235 | 89.2536 | 269.254 | 1.42109e-12 | 32.8 | 235 | 300 | 7700 | 70000 | 65545.5 | 65545.5 | 278.917 | 7711.24 | 7711.24
Enveloppe 166801 | 166801 | 0 | 0404 | 34.9866 | 235 | 89.9296 | 269.93 | 1.42109e-12 | 35 | 235 | 300 | 8200 | 70000 | 69885.8 | 69885.8 | 297.386 | 8221.86 | 8221.86
Enveloppe 163740 | 163740 | 1 | 0392 | 32.409 | 235 | 91.2648 | 271.265 | 1.42109e-12 | 32.4 | 235 | 300 | 7600 | 70000 | 64736.9 | 64736.9 | 275.476 | 7616.11 | 7616.11
Enveloppe 163643 | 163643 | 0 | 0389 | 96.6941 | 235 | 179.273 | 359.273 | 1.06581e-12 | 96.7 | 235 | 900 | 22700 | 200000 | 193147 | 193147 | 821.9 | 22723.1 | 22723.1
Enveloppe 163664 | 163664 | 0 | 0390 | 33.6683 | 235 | 90.5839 | 270.584 | 1.06581e-12 | 33.7 | 235 | 300 | 7900 | 70000 | 67252.4 | 67252.4 | 286.18 | 7912.04 | 7912.04
Enveloppe 164347 | 164347 | 1 | 0397 | 82.2551 | 230 | 0.213787 | 180.214 | -5 | 82.3 | 230 | 700 | 18900 | 170000 | 160809 | 60728.2 | 699.169 | 18918.7 | 7144.5
Enveloppe 163787 | 163787 | 0 | 0394 | 37.7481 | 235 | 89.7384 | 269.738 | 1.42109e-12 | 37.7 | 235 | 300 | 8900 | 80000 | 75401.8 | 75401.8 | 320.859 | 8870.8 | 8870.8
Enveloppe 163843 | 163843 | 1 | 0395 | 125.683 | 170 | 1.38839 | 181.388 | -65 | 125.7 | 170 | 1100 | 21400 | 190000 | 181612 | 79477.7 | 1068.31 | 21366.1 | 9350.32

# IfcWallStandardCase: default 87, Enveloppe courbe 169304
In: Niveau 2
Type - Material: <aucun> 8.7 cm
Description: Enveloppe courbe; Group: ...de matériaux et couleurs = Blanc; ...de matériaux et couleurs - 1 = Blanc; ...de matériaux et couleurs - 2 = Blanc; ...de stratigraphies = default
__RECOGNIZE__ - ID: 169304; TPLG: 367; TPLG_OD: 9001; GENERATE: 1
CTLG_EXTERNAL_LINK - 0, DocType: 2; 0, Tag: 0; 0, Crc: -746779066; 1, DocType: 2; 1, Tag: 100; 1, Crc: -746779066; 2, DocType: 2; 2, Tag: 200; 2, Crc: -746779066; 3, DocType: 9; 3, Tag: 0; 3, Crc: 596476440
IFC_PSET_PolygonOffset - polygonOffsetFactor: 2; polygonOffsetUnits: 2
IFC_Pset_Alignment - Alignment: 1
IFC_Pset_Strat_Detail_Align - ExternalFace: 0
IFC_Pset_Caractéristiques - ID: 169304; Numérotation: 07; Numéro niveau: 05; Titre niveau: Niveau 2; Stratigraphie: default [87,00]; Épaisseur: 8.7 cm; Épaisseur VARIABLE: no
IFC_Pset_Caractéristiques_FRUIT - Fruit: no; Taille: 0 cm
IFC_Pset_Géométrie_P1 (POINT initial) - Hauteur: 385.012 cm; Cote: 0 cm; Angle XY: 11.0763 deg
IFC_Pset_Géométrie_P2 (POINT final) - Hauteur: 413.562 cm; Cote: 0 cm; Angle XY: 191.076 deg
IFC_Pset_Géométrie - Rayon: 169.061 cm; Point arc: [-800,3; -119,4] cm; Centre: [-635,9; -109,7] cm; Angle de la Tangente: 3.04735 deg; Forme en Élévation: trapèze; Longueur: 32.6825 cm; Hauteur: 385.012 cm; Cote: 0 cm
IFC_Pset_Système de Référence Altimétrique_SUPÉRIEUR - NIVEAU: HAUT Mezzanine (Couverture 2134); delta: 0 cm; delta (P1): 0 cm; delta (P2): 0 cm; sous Niveau: <aucun>
IFC_Pset_Système de Référence Altimétrique_INFÉRIEUR - NIVEAU: Niveau 2 (Niveau 2 13545); delta: 0 cm; delta (P1): 0 cm; delta (P2): 0 cm; sous Niveau: <aucun>
IFC_Pset_Données Métré - Longueur Pied: 32.7 cm; Longueur Tête: 43.4 cm; Hauteur Maximale: 413.6 cm; Hauteur Minimale: 385 cm; Surface en Plan: 200 cm2; Surface Pied: 300 cm2; Surface Tête: 400 cm2; Surface de la Paroi: 13000 cm2; Volume: 120000 cm3
IFC_Pset_Matériaux - Face gauche: Blanc; Face droite: Blanc; Face latérale: Blanc
Pset_WallCommon - Reference: default [87,00] (..\VERTICALES\Default\)
BaseQuantities - GrossVolume: 113161 cm3; NetVolume: 113161 cm3; NominalLength: 32.6825 cm; NominalWidth: 8.67154 cm; NominalHeight: 399.287 cm; GrossFootprintArea: 283.408 cm2; NetFootprintArea: 283.408 cm2; GrossSideArea: 13049.7 cm2; NetSideArea: 13049.7 cm2

# IfcWallStandardCase: default 90 (499)
Type - Material: <aucun> 9 cm
__RECOGNIZE__ - GENERATE: 1
CTLG_EXTERNAL_LINK - 0, DocType: 2; 0, Tag: 0; 1, DocType: 2; 1, Tag: 100; 2, DocType: 2; 2, Tag: 200; 3, DocType: 9; 3, Tag: 0; 3, Crc: 923632929
IFC_PSET_PolygonOffset - polygonOffsetFactor: 2; polygonOffsetUnits: 2
IFC_Pset_Caractéristiques - Stratigraphie: default [90,00]; Épaisseur: 9 cm
IFC_Pset_Caractéristiques_FRUIT - Fruit: no; Taille: 0 cm
Pset_WallCommon - Reference: default [90,00] (..\VERTICALES\Default\)
Name | In | Description | __RECOGNIZE__, ID = IFC_Pset_Caractéristiques, ID | TPLG | TPLG_OD | 0, Crc | 1, Crc = 2, Crc | Alignment | ExternalFace | Numérotation | Numéro niveau | Titre niveau | Épaisseur VARIABLE | Forme en Élévation | Longueur (cm) = NominalLength (cm) | IFC_Pset_Géométrie, Hauteur (cm) = IFC_Pset_Géométrie_P1 (POINT initial), Hauteur (cm) | IFC_Pset_Géométrie, Cote (cm) = IFC_Pset_Géométrie_P1 (POINT initial), Cote (cm) = IFC_Pset_Géométrie_P2 (POINT final), Cote (cm) = IFC_Pset_Système de Référence Altimétrique_INFÉRIEUR, delta (cm) = IFC_Pset_Système de Référence Altimétrique_INFÉRIEUR, delta (P1) (cm) = IFC_Pset_Système de Référence Altimétrique_INFÉRIEUR, delta (P2) (cm) | IFC_Pset_Géométrie_P1 (POINT initial), Angle XY (deg) | IFC_Pset_Géométrie_P2 (POINT final), Hauteur (cm) | IFC_Pset_Géométrie_P2 (POINT final), Angle XY (deg) | IFC_Pset_Système de Référence Altimétrique_SUPÉRIEUR, NIVEAU | IFC_Pset_Système de Référence Altimétrique_SUPÉRIEUR, delta (cm) = IFC_Pset_Système de Référence Altimétrique_SUPÉRIEUR, delta (P1) (cm) = IFC_Pset_Système de Référence Altimétrique_SUPÉRIEUR, delta (P2) (cm) | IFC_Pset_Système de Référence Altimétrique_SUPÉRIEUR, sous Niveau | IFC_Pset_Système de Référence Altimétrique_INFÉRIEUR, NIVEAU | IFC_Pset_Système de Référence Altimétrique_INFÉRIEUR, sous Niveau | Longueur Pied (cm) | Longueur Tête (cm) | Hauteur Maximale (cm) | Hauteur Minimale (cm) | Surface en Plan (cm2) | Surface Pied (cm2) | Surface Tête (cm2) | Surface de la Paroi (cm2) | Volume (cm3) | Face gauche | Face droite = Face latérale | GrossVolume (cm3) | NetVolume (cm3) | NominalWidth (cm) | NominalHeight (cm) | GrossFootprintArea (cm2) = NetFootprintArea (cm2) | GrossSideArea (cm2) | NetSideArea (cm2) | Group
Enveloppe 568527 | Rez-de-Jardin | Enveloppe | 568527 | 366 | 9000 | 1977773087 | 1977773087 | 0 | 1 | 0882 | 02 | Rez-de-Jardin | no | rectangle | 214.998 | 266.4 | 7.4607e-12 | 90.5287 | 266.4 | 270.529 | HAUT Rez-de-Jardin (Rez-de-chaussée 1047) | -25 | <aucun> | Rez-de-Jardin (Rez-de-Jardin 15545) | <aucun> | 215 | 215 | 266.4 | 266.4 | 1900 | 1900 | 1900 | 57300 | 520000 | Ivoire clair | Ivoire clair | 515479 | 158545 | 9 | 266.4 | 1934.98 | 57275.5 | 17616.1 | ...de stratigraphies = default; ...de matériaux et couleurs = Ivoire clair; ...de matériaux et couleurs - 1 = Ivoire clair; ...de matériaux et couleurs - 2 = Ivoire clair
Enveloppe 575468 | Rez-de-Jardin | Enveloppe | 575468 | 366 | 9000 | 1977773087 | 1977773087 | 0 | 1 | 0883 | 02 | Rez-de-Jardin | no | rectangle | 40.8313 | 291.413 | 7.4607e-12 | 87.9418 | 291.413 | 267.942 | HAUT Rez-de-Jardin (Rez-de-chaussée 1047) | 0.0128504 | <aucun> | Rez-de-Jardin (Rez-de-Jardin 15545) | <aucun> | 40.8 | 40.8 | 291.4 | 291.4 | 400 | 400 | 400 | 11900 | 110000 | Ivoire clair | Ivoire clair | 107089 | 107089 | 9 | 291.413 | 367.482 | 11898.8 | 11898.8 | ...de stratigraphies = default; ...de matériaux et couleurs = Ivoire clair; ...de matériaux et couleurs - 1 = Ivoire clair; ...de matériaux et couleurs - 2 = Ivoire clair
Enveloppe 578381 | Rez-de-Jardin | Enveloppe | 578381 | 366 | 9000 | 1977773087 | 1977773087 | 1 | 1 | 0886 | 02 | Rez-de-Jardin | no | rectangle | 191.773 | 291.413 | -1.94511e-11 | 0.336177 | 291.413 | 180.336 | HAUT Rez-de-Jardin (Rez-de-chaussée 1047) | 0.0128504 | <aucun> | Rez-de-Jardin (Rez-de-Jardin 15545) | <aucun> | 191.8 | 191.8 | 291.4 | 291.4 | 1700 | 1700 | 1700 | 55900 | 500000 | Ivoire clair | Ivoire clair | 502967 | 502967 | 9 | 291.413 | 1725.96 | 55885.3 | 55885.3 | ...de stratigraphies = default; ...de matériaux et couleurs = Ivoire clair; ...de matériaux et couleurs - 1 = Ivoire clair; ...de matériaux et couleurs - 2 = Ivoire clair
Enveloppe 578498 | Rez-de-Jardin | Enveloppe | 578498 | 366 | 9000 | 1977773087 | 1977773087 | 0 | 1 | 0887 | 02 | Rez-de-Jardin | no | rectangle | 23.2637 | 291.413 | -1.94511e-11 | 93.6407 | 291.413 | 273.641 | HAUT Rez-de-Jardin (Rez-de-chaussée 1047) | 0.0128504 | <aucun> | Rez-de-Jardin (Rez-de-Jardin 15545) | <aucun> | 23.3 | 23.3 | 291.4 | 291.4 | 200 | 200 | 200 | 6800 | 60000 | Ivoire clair | Ivoire clair | 61014.1 | 61014.1 | 9 | 291.413 | 209.373 | 6779.34 | 6779.34 | ...de stratigraphies = default; ...de matériaux et couleurs = Ivoire clair; ...de matériaux et couleurs - 1 = Ivoire clair; ...de matériaux et couleurs - 2 = Ivoire clair
Enveloppe 575817 | Rez-de-Jardin | Enveloppe | 575817 | 366 | 9000 | 1977773087 | 1977773087 | 0 | 1 | 0884 | 02 | Rez-de-Jardin | no | rectangle | 180.59 | 271.4 | 7.4607e-12 | 90.1458 | 271.4 | 270.146 | HAUT Rez-de-Jardin (Rez-de-chaussée 1047) | -20 | <aucun> | Rez-de-Jardin (Rez-de-Jardin 15545) | <aucun> | 180.6 | 180.6 | 271.4 | 271.4 | 1600 | 1600 | 1600 | 49000 | 440000 | Ivoire clair | Ivoire clair | 441109 | 268687 | 9 | 271.4 | 1625.31 | 49012.1 | 29854.1 | ...de stratigraphies = default; ...de matériaux et couleurs = Ivoire clair; ...de matériaux et couleurs - 1 = Ivoire clair; ...de matériaux et couleurs - 2 = Ivoire clair
Enveloppe 578031 | Rez-de-Jardin | Enveloppe | 578031 | 366 | 9000 | 1977773087 | 1977773087 | 1 | 1 | 0885 | 02 | Rez-de-Jardin | no | rectangle | 27.5941 | 291.413 | -1.94511e-11 | 85.9192 | 291.413 | 265.919 | HAUT Rez-de-Jardin (Rez-de-chaussée 1047) | 0.0128504 | <aucun> | Rez-de-Jardin (Rez-de-Jardin 15545) | <aucun> | 27.6 | 27.6 | 291.4 | 291.4 | 200 | 200 | 200 | 8000 | 70000 | Ivoire clair | Ivoire clair | 72371.6 | 72371.6 | 9 | 291.413 | 248.347 | 8041.29 | 8041.29 | ...de stratigraphies = default; ...de matériaux et couleurs = Ivoire clair; ...de matériaux et couleurs - 1 = Ivoire clair; ...de matériaux et couleurs - 2 = Ivoire clair
Enveloppe 395010 | Rez-de-Jardin | Enveloppe | 395010 | 366 | 9000 | 1977773087 | 1977773087 | 0 | 1 | 0667 | 02 | Rez-de-Jardin | no | rectangle | 150.296 | 271.4 | -1.94511e-11 | 0.221025 | 271.4 | 180.221 | HAUT Rez-de-Jardin (Rez-de-chaussée 1047) | -20 | <aucun> | Rez-de-Jardin (Rez-de-Jardin 15545) | <aucun> | 150.3 | 150.3 | 271.4 | 271.4 | 1400 | 1400 | 1400 | 40800 | 370000 | Ivoire clair | Ivoire clair | 367114 | 367114 | 9 | 271.4 | 1352.67 | 40790.5 | 40790.5 | ...de stratigraphies = default; ...de matériaux et couleurs = Ivoire clair; ...de matériaux et couleurs - 1 = Ivoire clair; ...de matériaux et couleurs - 2 = Ivoire clair
Enveloppe 578761 | Rez-de-Jardin | Enveloppe | 578761 | 366 | 9000 | 1977773087 | 1977773087 | 1 | 1 | 0888 | 02 | Rez-de-Jardin | no | rectangle | 90.5975 | 291.413 | -1.94511e-11 | 0.336177 | 291.413 | 180.336 | HAUT Rez-de-Jardin (Rez-de-chaussée 1047) | 0.0128504 | <aucun> | Rez-de-Jardin (Rez-de-Jardin 15545) | <aucun> | 90.6 | 90.6 | 291.4 | 291.4 | 800 | 800 | 800 | 26400 | 240000 | Ivoire clair | Ivoire clair | 237612 | 237612 | 9 | 291.413 | 815.378 | 26401.3 | 26401.3 | ...de stratigraphies = default; ...de matériaux et couleurs = Ivoire clair; ...de matériaux et couleurs - 1 = Ivoire clair; ...de matériaux et couleurs - 2 = Ivoire clair
Enveloppe 2023371 | Rez-de-Jardin | Enveloppe | 2023371 | 366 | 9000 | 1977773087 | 1977773087 | 1 | 1 | 1174 | 02 | Rez-de-Jardin | no | rectangle | 23.0681 | 291.413 | -1.94511e-11 | 2.29888 | 291.413 | 182.299 | HAUT Rez-de-Jardin (Rez-de-chaussée 1047) | 0.0128504 | <aucun> | Rez-de-Jardin (Rez-de-Jardin 15545) | <aucun> | 23.1 | 23.1 | 291.4 | 291.4 | 200 | 200 | 200 | 6700 | 60000 | Ivoire clair | Ivoire clair | 60501.1 | 60501.1 | 9 | 291.413 | 207.613 | 6722.34 | 6722.34 | ...de stratigraphies = default; ...de matériaux et couleurs = Ivoire clair; ...de matériaux et couleurs - 1 = Ivoire clair; ...de matériaux et couleurs - 2 = Ivoire clair
Enveloppe 780458 | Rez-de-Jardin | Enveloppe | 780458 | 366 | 9000 | 1977773087 | 1977773087 | 1 | 0 | 1140 | 02 | Rez-de-Jardin | no | rectangle | 185.973 | 291.413 | 7.72715e-12 | 90.3035 | 291.413 | 270.304 | HAUT Rez-de-Jardin (Rez-de-chaussée 1047) | 0.0128504 | <aucun> | Rez-de-Jardin (Rez-de-Jardin 15545) | <aucun> | 186 | 186 | 291.4 | 291.4 | 1700 | 1700 | 1700 | 54200 | 490000 | Ivoire clair | Ivoire clair | 487756 | 487756 | 9 | 291.413 | 1673.76 | 54195.1 | 54195.1 | ...de stratigraphies = default; ...de matériaux et couleurs = Ivoire clair; ...de matériaux et couleurs - 1 = Ivoire clair; ...de matériaux et couleurs - 2 = Ivoire clair
Enveloppe 780002 | Rez-de-Jardin | Enveloppe | 780002 | 366 | 9000 | 1977773087 | 1977773087 | 1 | 0 | 1138 | 02 | Rez-de-Jardin | no | rectangle | 175.664 | 291.413 | 7.72715e-12 | 90.3035 | 291.413 | 270.304 | HAUT Rez-de-Jardin (Rez-de-chaussée 1047) | 0.0128504 | <aucun> | Rez-de-Jardin (Rez-de-Jardin 15545) | <aucun> | 175.7 | 175.7 | 291.4 | 291.4 | 1600 | 1600 | 1600 | 51200 | 460000 | Ivoire clair | Ivoire clair | 460717 | 460717 | 9 | 291.413 | 1580.98 | 51190.8 | 51190.8 | ...de stratigraphies = default; ...de matériaux et couleurs = Ivoire clair; ...de matériaux et couleurs - 1 = Ivoire clair; ...de matériaux et couleurs - 2 = Ivoire clair
Enveloppe 780141 | Rez-de-Jardin | Enveloppe | 780141 | 366 | 9000 | 1977773087 | 1977773087 | 0 | 0 | 1139 | 02 | Rez-de-Jardin | no | rectangle | 53 | 291.413 | 7.72715e-12 | 0.301265 | 291.413 | 180.301 | HAUT Rez-de-Jardin (Rez-de-chaussée 1047) | 0.0128504 | <aucun> | Rez-de-Jardin (Rez-de-Jardin 15545) | <aucun> | 53 | 53 | 291.4 | 291.4 | 500 | 500 | 500 | 15400 | 140000 | Ivoire clair | Ivoire clair | 139004 | 139004 | 9 | 291.413 | 477 | 15444.9 | 15444.9 | ...de stratigraphies = default; ...de matériaux et couleurs = Ivoire clair; ...de matériaux et couleurs - 1 = Ivoire clair; ...de matériaux et couleurs - 2 = Ivoire clair
Enveloppe 778648 | Rez-de-Jardin | Enveloppe | 778648 | 366 | 9000 | 1977773087 | 1977773087 | 0 | 0 | 1131 | 02 | Rez-de-Jardin | no | rectangle | 51.316 | 291.413 | 7.54952e-12 | 91.6557 | 291.413 | 271.656 | HAUT Rez-de-Jardin (Rez-de-chaussée 1047) | 0.0128504 | <aucun> | Rez-de-Jardin (Rez-de-Jardin 15545) | <aucun> | 51.3 | 51.3 | 291.4 | 291.4 | 500 | 500 | 500 | 14900 | 130000 | Ivoire clair | Ivoire clair | 134587 | 134587 | 9 | 291.413 | 461.844 | 14954.1 | 14954.1 | ...de stratigraphies = default; ...de matériaux et couleurs = Ivoire clair; ...de matériaux et couleurs - 1 = Ivoire clair; ...de matériaux et couleurs - 2 = Ivoire clair
Enveloppe 778649 | Rez-de-Jardin | Enveloppe | 778649 | 366 | 9000 | 1977773087 | 1977773087 | 0 | 0 | 1132 | 02 | Rez-de-Jardin | no | rectangle | 110.889 | 291.413 | -1.94511e-11 | 0.343229 | 291.413 | 180.343 | HAUT Rez-de-Jardin (Rez-de-chaussée 1047) | 0.0128504 | <aucun> | Rez-de-Jardin (Rez-de-Jardin 15545) | <aucun> | 110.9 | 110.9 | 291.4 | 291.4 | 1000 | 1000 | 1000 | 32300 | 290000 | Ivoire clair | Ivoire clair | 290831 | 200265 | 9 | 291.413 | 998.002 | 32314.5 | 22251.7 | ...de stratigraphies = default; ...de matériaux et couleurs = Ivoire clair; ...de matériaux et couleurs - 1 = Ivoire clair; ...de matériaux et couleurs - 2 = Ivoire clair
Enveloppe 779014 | Rez-de-Jardin | Enveloppe | 779014 | 366 | 9000 | 1977773087 | 1977773087 | 1 | 0 | 1133 | 02 | Rez-de-Jardin | no | rectangle | 176.185 | 291.413 | 7.54952e-12 | 0.441601 | 291.413 | 180.442 | HAUT Rez-de-Jardin (Rez-de-chaussée 1047) | 0.0128504 | <aucun> | Rez-de-Jardin (Rez-de-Jardin 15545) | <aucun> | 176.2 | 176.2 | 291.4 | 291.4 | 1600 | 1600 | 1600 | 51300 | 460000 | Ivoire clair | Ivoire clair | 462084 | 462084 | 9 | 291.413 | 1585.66 | 51342.6 | 51342.6 | ...de stratigraphies = default; ...de matériaux et couleurs = Ivoire clair; ...de matériaux et couleurs - 1 = Ivoire clair; ...de matériaux et couleurs - 2 = Ivoire clair
Enveloppe 779636 | Rez-de-Jardin | Enveloppe | 779636 | 366 | 9000 | 1977773087 | 1977773087 | 1 | 0 | 1136 | 02 | Rez-de-Jardin | no | rectangle | 53 | 291.413 | 7.72715e-12 | 0.301265 | 291.413 | 180.301 | HAUT Rez-de-Jardin (Rez-de-chaussée 1047) | 0.0128504 | <aucun> | Rez-de-Jardin (Rez-de-Jardin 15545) | <aucun> | 53 | 53 | 291.4 | 291.4 | 500 | 500 | 500 | 15400 | 140000 | Ivoire clair | Ivoire clair | 139004 | 139004 | 9 | 291.413 | 477 | 15444.9 | 15444.9 | ...de stratigraphies = default; ...de matériaux et couleurs = Ivoire clair; ...de matériaux et couleurs - 1 = Ivoire clair; ...de matériaux et couleurs - 2 = Ivoire clair
Enveloppe 779637 | Rez-de-Jardin | Enveloppe | 779637 | 366 | 9000 | 1977773087 | 1977773087 | 0 | 0 | 1137 | 02 | Rez-de-Jardin | no | rectangle | 115 | 291.413 | -1.94511e-11 | 90.3013 | 291.413 | 270.301 | HAUT Rez-de-Jardin (Rez-de-chaussée 1047) | 0.0128504 | <aucun> | Rez-de-Jardin (Rez-de-Jardin 15545) | <aucun> | 115 | 115 | 291.4 | 291.4 | 1000 | 1000 | 1000 | 33500 | 300000 | Ivoire clair | Ivoire clair | 301613 | 200696 | 9 | 291.413 | 1035 | 33512.5 | 22299.5 | ...de stratigraphies = default; ...de matériaux et couleurs = Ivoire clair; ...de matériaux et couleurs - 1 = Ivoire clair; ...de matériaux et couleurs - 2 = Ivoire clair
Enveloppe 779021 | Rez-de-Jardin | Enveloppe | 779021 | 366 | 9000 | 1977773087 | 1977773087 | 1 | 0 | 1134 | 02 | Rez-de-Jardin | no | rectangle | 51.5758 | 291.413 | 7.63833e-12 | 86.299 | 291.413 | 266.299 | HAUT Rez-de-Jardin (Rez-de-chaussée 1047) | 0.0128504 | <aucun> | Rez-de-Jardin (Rez-de-Jardin 15545) | <aucun> | 51.6 | 51.6 | 291.4 | 291.4 | 500 | 500 | 500 | 15000 | 140000 | Ivoire clair | Ivoire clair | 135269 | 135269 | 9 | 291.413 | 464.183 | 15029.9 | 15029.9 | ...de stratigraphies = default; ...de matériaux et couleurs = Ivoire clair; ...de matériaux et couleurs - 1 = Ivoire clair; ...de matériaux et couleurs - 2 = Ivoire clair
Enveloppe 779337 | Rez-de-Jardin | Enveloppe | 779337 | 366 | 9000 | 1977773087 | 1977773087 | 1 | 0 | 1135 | 02 | Rez-de-Jardin | no | rectangle | 174.906 | 291.413 | 7.63833e-12 | 0.196035 | 291.413 | 180.196 | HAUT Rez-de-Jardin (Rez-de-chaussée 1047) | 0.0128504 | <aucun> | Rez-de-Jardin (Rez-de-Jardin 15545) | <aucun> | 174.9 | 174.9 | 291.4 | 291.4 | 1600 | 1600 | 1600 | 51000 | 460000 | Ivoire clair | Ivoire clair | 458730 | 458730 | 9 | 291.413 | 1574.16 | 50970 | 50970 | ...de stratigraphies = default; ...de matériaux et couleurs = Ivoire clair; ...de matériaux et couleurs - 1 = Ivoire clair; ...de matériaux et couleurs - 2 = Ivoire clair
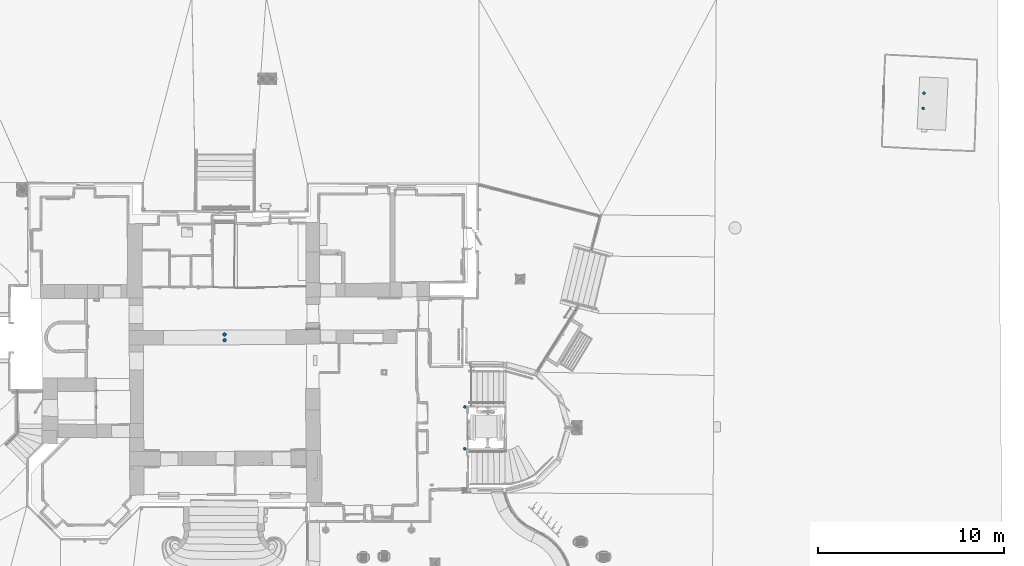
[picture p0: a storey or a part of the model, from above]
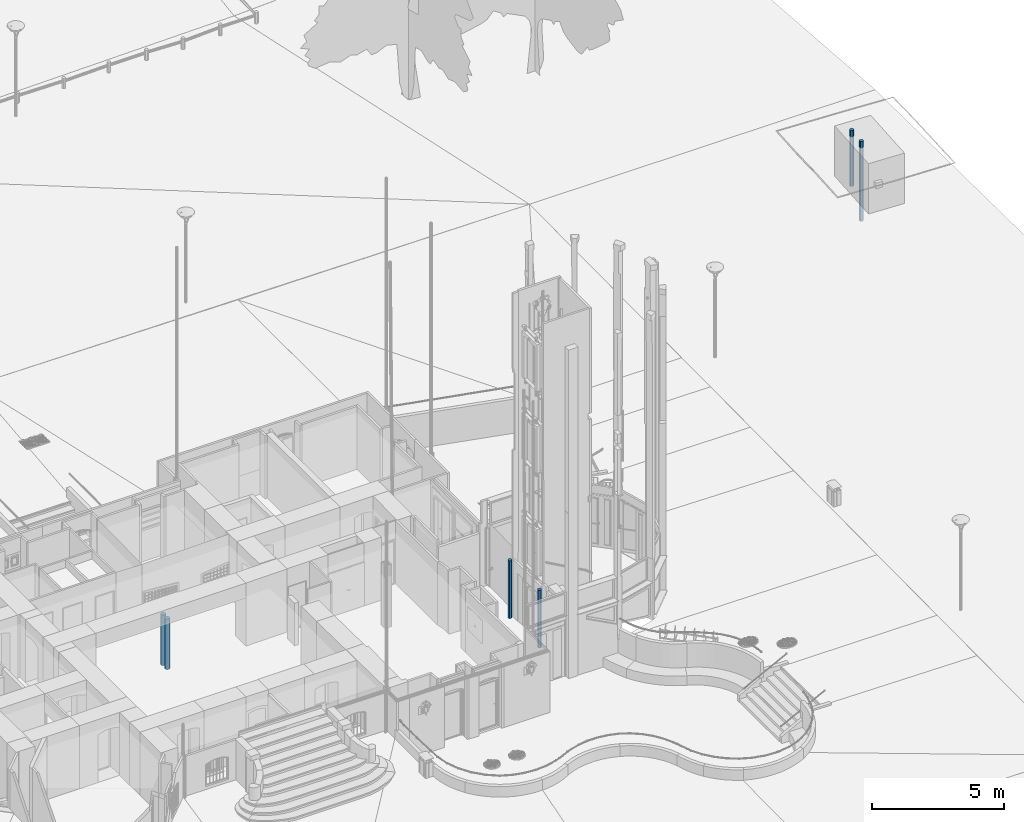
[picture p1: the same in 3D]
Properties of the parts of a building model (IFC2X3), part 29 of 37

# IfcWallStandardCase: default 90 (499)
Name | In | Description | __RECOGNIZE__, ID = IFC_Pset_Caractéristiques, ID | TPLG | TPLG_OD | 0, Crc | 1, Crc = 2, Crc | Alignment | ExternalFace | Numérotation | Numéro niveau | Titre niveau | Épaisseur VARIABLE | Forme en Élévation | Longueur (cm) = NominalLength (cm) | IFC_Pset_Géométrie, Hauteur (cm) = IFC_Pset_Géométrie_P1 (POINT initial), Hauteur (cm) | IFC_Pset_Géométrie, Cote (cm) = IFC_Pset_Géométrie_P1 (POINT initial), Cote (cm) = IFC_Pset_Géométrie_P2 (POINT final), Cote (cm) = IFC_Pset_Système de Référence Altimétrique_INFÉRIEUR, delta (cm) = IFC_Pset_Système de Référence Altimétrique_INFÉRIEUR, delta (P1) (cm) = IFC_Pset_Système de Référence Altimétrique_INFÉRIEUR, delta (P2) (cm) | IFC_Pset_Géométrie_P1 (POINT initial), Angle XY (deg) | IFC_Pset_Géométrie_P2 (POINT final), Hauteur (cm) | IFC_Pset_Géométrie_P2 (POINT final), Angle XY (deg) | IFC_Pset_Système de Référence Altimétrique_SUPÉRIEUR, NIVEAU | IFC_Pset_Système de Référence Altimétrique_SUPÉRIEUR, delta (cm) = IFC_Pset_Système de Référence Altimétrique_SUPÉRIEUR, delta (P1) (cm) = IFC_Pset_Système de Référence Altimétrique_SUPÉRIEUR, delta (P2) (cm) | IFC_Pset_Système de Référence Altimétrique_SUPÉRIEUR, sous Niveau | IFC_Pset_Système de Référence Altimétrique_INFÉRIEUR, NIVEAU | IFC_Pset_Système de Référence Altimétrique_INFÉRIEUR, sous Niveau | Longueur Pied (cm) | Longueur Tête (cm) | Hauteur Maximale (cm) | Hauteur Minimale (cm) | Surface en Plan (cm2) | Surface Pied (cm2) | Surface Tête (cm2) | Surface de la Paroi (cm2) | Volume (cm3) | Face gauche | Face droite = Face latérale | GrossVolume (cm3) | NetVolume (cm3) | NominalWidth (cm) | NominalHeight (cm) | GrossFootprintArea (cm2) = NetFootprintArea (cm2) | GrossSideArea (cm2) | NetSideArea (cm2) | Group
Enveloppe 596636 | Rez-de-Jardin | Enveloppe | 596636 | 366 | 9000 | 1977773087 | 1977773087 | 1 | 1 | 0937 | 02 | Rez-de-Jardin | no | rectangle | 176.756 | 291.413 | -1.94511e-11 | 89.6478 | 291.413 | 269.648 | HAUT Rez-de-Jardin (Rez-de-chaussée 1047) | 0.0128504 | <aucun> | Rez-de-Jardin (Rez-de-Jardin 15545) | <aucun> | 176.8 | 176.8 | 291.4 | 291.4 | 1600 | 1600 | 1600 | 51500 | 460000 | Ivoire clair | Ivoire clair | 463581 | 463581 | 9 | 291.413 | 1590.8 | 51509 | 51509 | ...de stratigraphies = default; ...de matériaux et couleurs = Ivoire clair; ...de matériaux et couleurs - 1 = Ivoire clair; ...de matériaux et couleurs - 2 = Ivoire clair
Enveloppe 596726 | Rez-de-Jardin | Enveloppe | 596726 | 366 | 9000 | 1977773087 | 1977773087 | 1 | 1 | 0938 | 02 | Rez-de-Jardin | no | rectangle | 20 | 291.413 | -1.94511e-11 | 95.1818 | 291.413 | 275.182 | HAUT Rez-de-Jardin (Rez-de-chaussée 1047) | 0.0128504 | <aucun> | Rez-de-Jardin (Rez-de-Jardin 15545) | <aucun> | 20 | 20 | 291.4 | 291.4 | 200 | 200 | 200 | 5800 | 50000 | Ivoire clair | Ivoire clair | 52454.4 | 52454.4 | 9 | 291.413 | 180 | 5828.26 | 5828.26 | ...de stratigraphies = default; ...de matériaux et couleurs = Ivoire clair; ...de matériaux et couleurs - 1 = Ivoire clair; ...de matériaux et couleurs - 2 = Ivoire clair
Enveloppe 594285 | Rez-de-Jardin | Enveloppe | 594285 | 366 | 9000 | 1977773087 | 1977773087 | 1 | 1 | 0935 | 02 | Rez-de-Jardin | yes | rectangle | 106.995 | 291.413 | -1.94511e-11 | 90.3425 | 291.413 | 270.343 | HAUT Rez-de-Jardin (Rez-de-chaussée 1047) | 0.0128504 | <aucun> | Rez-de-Jardin (Rez-de-Jardin 15545) | <aucun> | 107 | 107 | 291.4 | 291.4 | 1000 | 1000 | 1000 | 31200 | 280000 | Ivoire clair | Ivoire clair | 284843 | 87075.4 | 9.13549 | 291.413 | 977.455 | 31179.9 | 9525.3 | ...de stratigraphies = default; ...de matériaux et couleurs = Ivoire clair; ...de matériaux et couleurs - 1 = Ivoire clair; ...de matériaux et couleurs - 2 = Ivoire clair
Enveloppe 591976 | Rez-de-Jardin | Enveloppe | 591976 | 366 | 9000 | 1977773087 | 1977773087 | 0 | 0 | 0928 | 02 | Rez-de-Jardin | no | rectangle | 50.2082 | 291.413 | -1.94511e-11 | 86.0444 | 291.413 | 266.044 | HAUT Rez-de-Jardin (Rez-de-chaussée 1047) | 0.0128504 | <aucun> | Rez-de-Jardin (Rez-de-Jardin 15545) | <aucun> | 50.2 | 50.2 | 291.4 | 291.4 | 500 | 500 | 500 | 14600 | 130000 | Ivoire clair | Ivoire clair | 131682 | 131682 | 9 | 291.413 | 451.874 | 14631.3 | 14631.3 | ...de stratigraphies = default; ...de matériaux et couleurs = Ivoire clair; ...de matériaux et couleurs - 1 = Ivoire clair; ...de matériaux et couleurs - 2 = Ivoire clair
Enveloppe 591977 | Rez-de-Jardin | Enveloppe | 591977 | 366 | 9000 | 1977773087 | 1977773087 | 1 | 0 | 0929 | 02 | Rez-de-Jardin | no | rectangle | 106.554 | 291.413 | -1.94511e-11 | 0.212347 | 291.413 | 180.212 | HAUT Rez-de-Jardin (Rez-de-chaussée 1047) | 0.0128504 | <aucun> | Rez-de-Jardin (Rez-de-Jardin 15545) | <aucun> | 106.6 | 106.6 | 291.4 | 291.4 | 1000 | 1000 | 1000 | 31100 | 280000 | Ivoire clair | Ivoire clair | 279462 | 92538.2 | 9 | 291.413 | 958.987 | 31051.3 | 10282 | ...de stratigraphies = default; ...de matériaux et couleurs = Ivoire clair; ...de matériaux et couleurs - 1 = Ivoire clair; ...de matériaux et couleurs - 2 = Ivoire clair
Enveloppe 591621 | Rez-de-Jardin | Enveloppe | 591621 | 366 | 9000 | 1977773087 | 1977773087 | 1 | 0 | 0926 | 02 | Rez-de-Jardin | no | rectangle | 107.379 | 291.413 | -1.94511e-11 | 0.212347 | 291.413 | 180.212 | HAUT Rez-de-Jardin (Rez-de-chaussée 1047) | 0.0128504 | <aucun> | Rez-de-Jardin (Rez-de-Jardin 15545) | <aucun> | 107.4 | 107.4 | 291.4 | 291.4 | 1000 | 1000 | 1000 | 31300 | 280000 | Ivoire clair | Ivoire clair | 281626 | 93568.6 | 9 | 291.413 | 966.415 | 31291.8 | 10396.5 | ...de stratigraphies = default; ...de matériaux et couleurs = Ivoire clair; ...de matériaux et couleurs - 1 = Ivoire clair; ...de matériaux et couleurs - 2 = Ivoire clair
Enveloppe 591885 | Rez-de-Jardin | Enveloppe | 591885 | 366 | 9000 | 1977773087 | 1977773087 | 0 | 0 | 0927 | 02 | Rez-de-Jardin | no | rectangle | 118.68 | 291.413 | -1.94511e-11 | 0.175945 | 291.413 | 180.176 | HAUT Rez-de-Jardin (Rez-de-chaussée 1047) | 0.0128504 | <aucun> | Rez-de-Jardin (Rez-de-Jardin 15545) | <aucun> | 118.7 | 118.7 | 291.4 | 291.4 | 1100 | 1100 | 1100 | 34600 | 310000 | Ivoire clair | Ivoire clair | 311265 | 311265 | 9 | 291.413 | 1068.12 | 34585 | 34585 | ...de stratigraphies = default; ...de matériaux et couleurs = Ivoire clair; ...de matériaux et couleurs - 1 = Ivoire clair; ...de matériaux et couleurs - 2 = Ivoire clair
Enveloppe 593062 | Rez-de-Jardin | Enveloppe | 593062 | 366 | 9000 | 1977773087 | 1977773087 | 0 | 0 | 0930 | 02 | Rez-de-Jardin | no | rectangle | 47.9643 | 291.413 | -1.94511e-11 | 2.81945 | 291.413 | 182.819 | HAUT Rez-de-Jardin (Rez-de-chaussée 1047) | 0.0128504 | <aucun> | Rez-de-Jardin (Rez-de-Jardin 15545) | <aucun> | 48 | 48 | 291.4 | 291.4 | 400 | 400 | 400 | 14000 | 130000 | Ivoire clair | Ivoire clair | 125797 | 125797 | 9 | 291.413 | 431.679 | 13977.4 | 13977.4 | ...de stratigraphies = default; ...de matériaux et couleurs = Ivoire clair; ...de matériaux et couleurs - 1 = Ivoire clair; ...de matériaux et couleurs - 2 = Ivoire clair
Enveloppe 593879 | Rez-de-Jardin | Enveloppe | 593879 | 366 | 9000 | 1977773087 | 1977773087 | 0 | 1 | 0933 | 02 | Rez-de-Jardin | yes | rectangle | 47.8239 | 291.413 | -1.94511e-11 | 178.774 | 291.413 | 358.774 | HAUT Rez-de-Jardin (Rez-de-chaussée 1047) | 0.0128504 | <aucun> | Rez-de-Jardin (Rez-de-Jardin 15545) | <aucun> | 47.8 | 47.8 | 291.4 | 291.4 | 400 | 400 | 400 | 13900 | 130000 | Ivoire clair | Ivoire clair | 125429 | 125429 | 9 | 291.413 | 430.415 | 13936.5 | 13936.5 | ...de stratigraphies = default; ...de matériaux et couleurs = Ivoire clair; ...de matériaux et couleurs - 1 = Ivoire clair; ...de matériaux et couleurs - 2 = Ivoire clair
Enveloppe 594284 | Rez-de-Jardin | Enveloppe | 594284 | 366 | 9000 | 1977773087 | 1977773087 | 0 | 1 | 0934 | 02 | Rez-de-Jardin | no | rectangle | 48.5756 | 291.413 | -1.94511e-11 | 178.469 | 291.413 | 358.469 | HAUT Rez-de-Jardin (Rez-de-chaussée 1047) | 0.0128504 | <aucun> | Rez-de-Jardin (Rez-de-Jardin 15545) | <aucun> | 48.6 | 48.6 | 291.4 | 291.4 | 400 | 400 | 400 | 14200 | 130000 | Ivoire clair | Ivoire clair | 127400 | 127400 | 9 | 291.413 | 437.18 | 14155.6 | 14155.6 | ...de stratigraphies = default; ...de matériaux et couleurs = Ivoire clair; ...de matériaux et couleurs - 1 = Ivoire clair; ...de matériaux et couleurs - 2 = Ivoire clair
Enveloppe 593434 | Rez-de-Jardin | Enveloppe | 593434 | 366 | 9000 | 1977773087 | 1977773087 | 0 | 1 | 0931 | 02 | Rez-de-Jardin | yes | rectangle | 34.1741 | 291.413 | -1.94511e-11 | 89.581 | 291.413 | 269.581 | HAUT Rez-de-Jardin (Rez-de-chaussée 1047) | 0.0128504 | <aucun> | Rez-de-Jardin (Rez-de-Jardin 15545) | <aucun> | 34.2 | 34.2 | 291.4 | 291.4 | 300 | 300 | 300 | 10000 | 90000 | Ivoire clair | Ivoire clair | 89629.2 | 89629.2 | 9 | 291.413 | 307.567 | 9958.8 | 9958.8 | ...de stratigraphies = default; ...de matériaux et couleurs = Ivoire clair; ...de matériaux et couleurs - 1 = Ivoire clair; ...de matériaux et couleurs - 2 = Ivoire clair
Enveloppe 593609 | Rez-de-Jardin | Enveloppe | 593609 | 366 | 9000 | 1977773087 | 1977773087 | 0 | 1 | 0932 | 02 | Rez-de-Jardin | yes | rectangle | 53.7962 | 291.413 | -1.94511e-11 | 2.10164 | 291.413 | 182.102 | HAUT Rez-de-Jardin (Rez-de-chaussée 1047) | 0.0128504 | <aucun> | Rez-de-Jardin (Rez-de-Jardin 15545) | <aucun> | 53.8 | 53.8 | 291.4 | 291.4 | 500 | 500 | 500 | 15700 | 140000 | Ivoire clair | Ivoire clair | 141092 | 141092 | 9 | 291.413 | 484.166 | 15676.9 | 15676.9 | ...de stratigraphies = default; ...de matériaux et couleurs = Ivoire clair; ...de matériaux et couleurs - 1 = Ivoire clair; ...de matériaux et couleurs - 2 = Ivoire clair
Enveloppe 591620 | Rez-de-Jardin | Enveloppe | 591620 | 366 | 9000 | 1977773087 | 1977773087 | 0 | 0 | 0925 | 02 | Rez-de-Jardin | no | rectangle | 49.1686 | 291.413 | -1.94511e-11 | 85.6551 | 291.413 | 265.655 | HAUT Rez-de-Jardin (Rez-de-chaussée 1047) | 0.0128504 | <aucun> | Rez-de-Jardin (Rez-de-Jardin 15545) | <aucun> | 49.2 | 49.2 | 291.4 | 291.4 | 400 | 400 | 400 | 14300 | 130000 | Ivoire clair | Ivoire clair | 128955 | 128955 | 9 | 291.413 | 442.517 | 14328.4 | 14328.4 | ...de stratigraphies = default; ...de matériaux et couleurs = Ivoire clair; ...de matériaux et couleurs - 1 = Ivoire clair; ...de matériaux et couleurs - 2 = Ivoire clair
Enveloppe 582876 | Rez-de-Jardin | Enveloppe | 582876 | 366 | 9000 | 1977773087 | 1977773087 | 0 | 1 | 0900 | 02 | Rez-de-Jardin | no | rectangle | 49.8093 | 291.413 | -1.94511e-11 | 1.59384 | 291.413 | 181.594 | HAUT Rez-de-Jardin (Rez-de-chaussée 1047) | 0.0128504 | <aucun> | Rez-de-Jardin (Rez-de-Jardin 15545) | <aucun> | 49.8 | 49.8 | 291.4 | 291.4 | 400 | 400 | 400 | 14500 | 130000 | Ivoire clair | Ivoire clair | 130636 | 130636 | 9 | 291.413 | 448.284 | 14515.1 | 14515.1 | ...de stratigraphies = default; ...de matériaux et couleurs = Ivoire clair; ...de matériaux et couleurs - 1 = Ivoire clair; ...de matériaux et couleurs - 2 = Ivoire clair
Enveloppe 583646 | Rez-de-Jardin | Enveloppe | 583646 | 366 | 9000 | 1977773087 | 1977773087 | 1 | 0 | 0901 | 02 | Rez-de-Jardin | yes | rectangle | 39.4788 | 291.413 | -1.94511e-11 | 134.657 | 291.413 | 314.657 | HAUT Rez-de-Jardin (Rez-de-chaussée 1047) | 0.0128504 | <aucun> | Rez-de-Jardin (Rez-de-Jardin 15545) | <aucun> | 39.5 | 39.5 | 291.4 | 291.4 | 400 | 400 | 400 | 11500 | 100000 | Ivoire clair | Ivoire clair | 103542 | 103542 | 9 | 291.413 | 355.309 | 11504.7 | 11504.7 | ...de stratigraphies = default; ...de matériaux et couleurs = Ivoire clair; ...de matériaux et couleurs - 1 = Ivoire clair; ...de matériaux et couleurs - 2 = Ivoire clair
Enveloppe 581797 | Rez-de-Jardin | Enveloppe | 581797 | 366 | 9000 | 1977773087 | 1977773087 | 0 | 1 | 0898 | 02 | Rez-de-Jardin | no | rectangle | 40.0144 | 291.413 | -1.94511e-11 | 92.1995 | 291.413 | 272.199 | HAUT Rez-de-Jardin (Rez-de-chaussée 1047) | 0.0128504 | <aucun> | Rez-de-Jardin (Rez-de-Jardin 15545) | <aucun> | 40 | 40 | 291.4 | 291.4 | 400 | 400 | 400 | 11700 | 110000 | Ivoire clair | Ivoire clair | 104946 | 104946 | 9 | 291.413 | 360.129 | 11660.7 | 11660.7 | ...de stratigraphies = default; ...de matériaux et couleurs = Ivoire clair; ...de matériaux et couleurs - 1 = Ivoire clair; ...de matériaux et couleurs - 2 = Ivoire clair
Enveloppe 582874 | Rez-de-Jardin | Enveloppe | 582874 | 366 | 9000 | 1977773087 | 1977773087 | 0 | 1 | 0899 | 02 | Rez-de-Jardin | no | rectangle | 49.5135 | 291.413 | -1.94511e-11 | 174.186 | 291.413 | 354.186 | HAUT Rez-de-Jardin (Rez-de-chaussée 1047) | 0.0128504 | <aucun> | Rez-de-Jardin (Rez-de-Jardin 15545) | <aucun> | 49.5 | 49.5 | 291.4 | 291.4 | 400 | 400 | 400 | 14400 | 130000 | Ivoire clair | Ivoire clair | 129860 | 129860 | 9 | 291.413 | 445.622 | 14428.9 | 14428.9 | ...de stratigraphies = default; ...de matériaux et couleurs = Ivoire clair; ...de matériaux et couleurs - 1 = Ivoire clair; ...de matériaux et couleurs - 2 = Ivoire clair
Enveloppe 583737 | Rez-de-Jardin | Enveloppe | 583737 | 366 | 9000 | 1977773087 | 1977773087 | 1 | 0 | 0902 | 02 | Rez-de-Jardin | yes | rectangle | 56.1149 | 291.413 | -1.94511e-11 | 48.4983 | 291.413 | 228.498 | HAUT Rez-de-Jardin (Rez-de-chaussée 1047) | 0.0128504 | <aucun> | Rez-de-Jardin (Rez-de-Jardin 15545) | <aucun> | 56.1 | 56.1 | 291.4 | 291.4 | 500 | 500 | 500 | 16300 | 150000 | Ivoire clair | Ivoire clair | 147173 | 147173 | 9 | 291.413 | 505.034 | 16352.6 | 16352.6 | ...de stratigraphies = default; ...de matériaux et couleurs = Ivoire clair; ...de matériaux et couleurs - 1 = Ivoire clair; ...de matériaux et couleurs - 2 = Ivoire clair
Enveloppe 584301 | Rez-de-Jardin | Enveloppe | 584301 | 366 | 9000 | 1977773087 | 1977773087 | 0 | 0 | 0905 | 02 | Rez-de-Jardin | yes | rectangle | 55.9949 | 291.413 | -1.94511e-11 | 44.8839 | 291.413 | 224.884 | HAUT Rez-de-Jardin (Rez-de-chaussée 1047) | 0.0128504 | <aucun> | Rez-de-Jardin (Rez-de-Jardin 15545) | <aucun> | 56 | 56 | 291.4 | 291.4 | 500 | 500 | 500 | 16300 | 150000 | Ivoire clair | Ivoire clair | 146859 | 146859 | 9 | 291.413 | 503.954 | 16317.6 | 16317.6 | ...de stratigraphies = default; ...de matériaux et couleurs = Ivoire clair; ...de matériaux et couleurs - 1 = Ivoire clair; ...de matériaux et couleurs - 2 = Ivoire clair
Enveloppe 584799 | Rez-de-Jardin | Enveloppe | 584799 | 366 | 9000 | 1977773087 | 1977773087 | 0 | 0 | 0906 | 02 | Rez-de-Jardin | no | rectangle | 55.8306 | 291.413 | -1.94511e-11 | 45.9279 | 291.413 | 225.928 | HAUT Rez-de-Jardin (Rez-de-chaussée 1047) | 0.0128504 | <aucun> | Rez-de-Jardin (Rez-de-Jardin 15545) | <aucun> | 55.8 | 55.8 | 291.4 | 291.4 | 500 | 500 | 500 | 16300 | 150000 | Ivoire clair | Ivoire clair | 146428 | 146428 | 9 | 291.413 | 502.475 | 16269.8 | 16269.8 | ...de stratigraphies = default; ...de matériaux et couleurs = Ivoire clair; ...de matériaux et couleurs - 1 = Ivoire clair; ...de matériaux et couleurs - 2 = Ivoire clair
Enveloppe 583738 | Rez-de-Jardin | Enveloppe | 583738 | 366 | 9000 | 1977773087 | 1977773087 | 0 | 0 | 0903 | 02 | Rez-de-Jardin | yes | rectangle | 113.462 | 291.413 | -1.94511e-11 | 134.676 | 291.413 | 314.676 | HAUT Rez-de-Jardin (Rez-de-chaussée 1047) | 0.0128504 | <aucun> | Rez-de-Jardin (Rez-de-Jardin 15545) | <aucun> | 113.5 | 113.5 | 291.4 | 291.4 | 1000 | 1000 | 1000 | 33100 | 300000 | Ivoire clair | Ivoire clair | 297579 | 201041 | 9 | 291.413 | 1021.16 | 33064.3 | 22337.8 | ...de stratigraphies = default; ...de matériaux et couleurs = Ivoire clair; ...de matériaux et couleurs - 1 = Ivoire clair; ...de matériaux et couleurs - 2 = Ivoire clair
Enveloppe 583999 | Rez-de-Jardin | Enveloppe | 583999 | 366 | 9000 | 1977773087 | 1977773087 | 1 | 0 | 0904 | 02 | Rez-de-Jardin | yes | rectangle | 40.4251 | 291.413 | -1.94511e-11 | 134.657 | 291.413 | 314.657 | HAUT Rez-de-Jardin (Rez-de-chaussée 1047) | 0.0128504 | <aucun> | Rez-de-Jardin (Rez-de-Jardin 15545) | <aucun> | 40.4 | 40.4 | 291.4 | 291.4 | 400 | 400 | 400 | 11800 | 110000 | Ivoire clair | Ivoire clair | 106024 | 106024 | 9 | 291.413 | 363.826 | 11780.4 | 11780.4 | ...de stratigraphies = default; ...de matériaux et couleurs = Ivoire clair; ...de matériaux et couleurs - 1 = Ivoire clair; ...de matériaux et couleurs - 2 = Ivoire clair
Enveloppe 579415 | Rez-de-Jardin | Enveloppe | 579415 | 366 | 9000 | 1977773087 | 1977773087 | 1 | 1 | 0891 | 02 | Rez-de-Jardin | no | rectangle | 182.353 | 291.413 | -1.94511e-11 | 0.51564 | 291.413 | 180.516 | HAUT Rez-de-Jardin (Rez-de-chaussée 1047) | 0.0128504 | <aucun> | Rez-de-Jardin (Rez-de-Jardin 15545) | <aucun> | 182.4 | 182.4 | 291.4 | 291.4 | 1600 | 1600 | 1600 | 53200 | 480000 | Ivoire clair | Ivoire clair | 478261 | 478261 | 9 | 291.413 | 1641.18 | 53140.1 | 53140.1 | ...de stratigraphies = default; ...de matériaux et couleurs = Ivoire clair; ...de matériaux et couleurs - 1 = Ivoire clair; ...de matériaux et couleurs - 2 = Ivoire clair
Enveloppe 579507 | Rez-de-Jardin | Enveloppe | 579507 | 366 | 9000 | 1977773087 | 1977773087 | 0 | 1 | 0892 | 02 | Rez-de-Jardin | no | rectangle | 55.0799 | 291.413 | -1.94511e-11 | 94.1757 | 291.413 | 274.176 | HAUT Rez-de-Jardin (Rez-de-chaussée 1047) | 0.0128504 | <aucun> | Rez-de-Jardin (Rez-de-Jardin 15545) | <aucun> | 55.1 | 55.1 | 291.4 | 291.4 | 500 | 500 | 500 | 16100 | 140000 | Ivoire clair | Ivoire clair | 144459 | 144459 | 9 | 291.413 | 495.719 | 16051 | 16051 | ...de stratigraphies = default; ...de matériaux et couleurs = Ivoire clair; ...de matériaux et couleurs - 1 = Ivoire clair; ...de matériaux et couleurs - 2 = Ivoire clair
Enveloppe 579019 | Rez-de-Jardin | Enveloppe | 579019 | 366 | 9000 | 1977773087 | 1977773087 | 1 | 1 | 0889 | 02 | Rez-de-Jardin | no | rectangle | 35.1856 | 291.413 | -1.94511e-11 | 85.9192 | 291.413 | 265.919 | HAUT Rez-de-Jardin (Rez-de-chaussée 1047) | 0.0128504 | <aucun> | Rez-de-Jardin (Rez-de-Jardin 15545) | <aucun> | 35.2 | 35.2 | 291.4 | 291.4 | 300 | 300 | 300 | 10300 | 90000 | Ivoire clair | Ivoire clair | 92281.9 | 92281.9 | 9 | 291.413 | 316.67 | 10253.5 | 10253.5 | ...de stratigraphies = default; ...de matériaux et couleurs = Ivoire clair; ...de matériaux et couleurs - 1 = Ivoire clair; ...de matériaux et couleurs - 2 = Ivoire clair
Enveloppe 579508 | Rez-de-Jardin | Enveloppe | 579508 | 366 | 9000 | 1977773087 | 1977773087 | 0 | 1 | 0893 | 02 | Rez-de-Jardin | no | rectangle | 103.172 | 291.413 | -1.94511e-11 | 0.531271 | 291.413 | 180.531 | HAUT Rez-de-Jardin (Rez-de-chaussée 1047) | 0.0128504 | <aucun> | Rez-de-Jardin (Rez-de-Jardin 15545) | <aucun> | 103.2 | 103.2 | 291.4 | 291.4 | 900 | 900 | 900 | 30100 | 270000 | Ivoire clair | Ivoire clair | 270590 | 212182 | 9 | 291.413 | 928.545 | 30065.6 | 23575.7 | ...de stratigraphies = default; ...de matériaux et couleurs = Ivoire clair; ...de matériaux et couleurs - 1 = Ivoire clair; ...de matériaux et couleurs - 2 = Ivoire clair
Enveloppe 581669 | Rez-de-Jardin | Enveloppe | 581669 | 366 | 9000 | 1977773087 | 1977773087 | 1 | 1 | 0897 | 02 | Rez-de-Jardin | no | rectangle | 40.1922 | 291.413 | -1.94511e-11 | 89.4457 | 291.413 | 269.446 | HAUT Rez-de-Jardin (Rez-de-chaussée 1047) | 0.0128504 | <aucun> | Rez-de-Jardin (Rez-de-Jardin 15545) | <aucun> | 40.2 | 40.2 | 291.4 | 291.4 | 400 | 400 | 400 | 11700 | 110000 | Ivoire clair | Ivoire clair | 105413 | 105413 | 9 | 291.413 | 361.73 | 11712.5 | 11712.5 | ...de stratigraphies = default; ...de matériaux et couleurs = Ivoire clair; ...de matériaux et couleurs - 1 = Ivoire clair; ...de matériaux et couleurs - 2 = Ivoire clair
Enveloppe 579867 | Rez-de-Jardin | Enveloppe | 579867 | 366 | 9000 | 1977773087 | 1977773087 | 1 | 1 | 0894 | 02 | Rez-de-Jardin | no | rectangle | 87.6875 | 291.413 | -1.94511e-11 | 0.51564 | 291.413 | 180.516 | HAUT Rez-de-Jardin (Rez-de-chaussée 1047) | 0.0128504 | <aucun> | Rez-de-Jardin (Rez-de-Jardin 15545) | <aucun> | 87.7 | 87.7 | 291.4 | 291.4 | 800 | 800 | 800 | 25600 | 230000 | Ivoire clair | Ivoire clair | 229980 | 229980 | 9 | 291.413 | 789.188 | 25553.3 | 25553.3 | ...de stratigraphies = default; ...de matériaux et couleurs = Ivoire clair; ...de matériaux et couleurs - 1 = Ivoire clair; ...de matériaux et couleurs - 2 = Ivoire clair
Enveloppe 579958 | Rez-de-Jardin | Enveloppe | 579958 | 366 | 9000 | 1977773087 | 1977773087 | 1 | 1 | 0895 | 02 | Rez-de-Jardin | no | rectangle | 58.0147 | 291.413 | -1.94511e-11 | 87.3066 | 291.413 | 267.307 | HAUT Rez-de-Jardin (Rez-de-chaussée 1047) | 0.0128504 | <aucun> | Rez-de-Jardin (Rez-de-Jardin 15545) | <aucun> | 58 | 58 | 291.4 | 291.4 | 500 | 500 | 500 | 16900 | 150000 | Ivoire clair | Ivoire clair | 152156 | 152156 | 9 | 291.413 | 522.132 | 16906.2 | 16906.2 | ...de stratigraphies = default; ...de matériaux et couleurs = Ivoire clair; ...de matériaux et couleurs - 1 = Ivoire clair; ...de matériaux et couleurs - 2 = Ivoire clair
Enveloppe 589720 | Rez-de-Jardin | Enveloppe | 589720 | 366 | 9000 | 1977773087 | 1977773087 | 0 | 1 | 0918 | 02 | Rez-de-Jardin | no | rectangle | 117.835 | 291.413 | -1.94511e-11 | 0.0844895 | 291.413 | 180.084 | HAUT Rez-de-Jardin (Rez-de-chaussée 1047) | 0.0128504 | <aucun> | Rez-de-Jardin (Rez-de-Jardin 15545) | <aucun> | 117.8 | 117.8 | 291.4 | 291.4 | 1100 | 1100 | 1100 | 34300 | 310000 | Ivoire clair | Ivoire clair | 309048 | 190166 | 9 | 291.413 | 1060.51 | 34338.6 | 21129.6 | ...de stratigraphies = default; ...de matériaux et couleurs = Ivoire clair; ...de matériaux et couleurs - 1 = Ivoire clair; ...de matériaux et couleurs - 2 = Ivoire clair
Enveloppe 589975 | Rez-de-Jardin | Enveloppe | 589975 | 366 | 9000 | 1977773087 | 1977773087 | 1 | 1 | 0919 | 02 | Rez-de-Jardin | no | rectangle | 45.0999 | 291.413 | -1.94511e-11 | 86.4803 | 291.413 | 266.48 | HAUT Rez-de-Jardin (Rez-de-chaussée 1047) | 0.0128504 | <aucun> | Rez-de-Jardin (Rez-de-Jardin 15545) | <aucun> | 45.1 | 45.1 | 291.4 | 291.4 | 400 | 400 | 400 | 13100 | 120000 | Ivoire clair | Ivoire clair | 118284 | 118284 | 9 | 291.413 | 405.899 | 13142.7 | 13142.7 | ...de stratigraphies = default; ...de matériaux et couleurs = Ivoire clair; ...de matériaux et couleurs - 1 = Ivoire clair; ...de matériaux et couleurs - 2 = Ivoire clair
Enveloppe 588990 | Rez-de-Jardin | Enveloppe | 588990 | 366 | 9000 | 1977773087 | 1977773087 | 1 | 1 | 0916 | 02 | Rez-de-Jardin | no | rectangle | 38.7152 | 291.413 | -1.94511e-11 | 85.8982 | 291.413 | 265.898 | HAUT Rez-de-Jardin (Rez-de-chaussée 1047) | 0.0128504 | <aucun> | Rez-de-Jardin (Rez-de-Jardin 15545) | <aucun> | 38.7 | 38.7 | 291.4 | 291.4 | 300 | 300 | 300 | 11300 | 100000 | Ivoire clair | Ivoire clair | 101539 | 101539 | 9 | 291.413 | 348.437 | 11282.1 | 11282.1 | ...de stratigraphies = default; ...de matériaux et couleurs = Ivoire clair; ...de matériaux et couleurs - 1 = Ivoire clair; ...de matériaux et couleurs - 2 = Ivoire clair
Enveloppe 589719 | Rez-de-Jardin | Enveloppe | 589719 | 366 | 9000 | 1977773087 | 1977773087 | 0 | 1 | 0917 | 02 | Rez-de-Jardin | no | rectangle | 36.0269 | 291.413 | -1.94511e-11 | 92.2989 | 291.413 | 272.299 | HAUT Rez-de-Jardin (Rez-de-chaussée 1047) | 0.0128504 | <aucun> | Rez-de-Jardin (Rez-de-Jardin 15545) | <aucun> | 36 | 36 | 291.4 | 291.4 | 300 | 300 | 300 | 10500 | 90000 | Ivoire clair | Ivoire clair | 94488.4 | 94488.4 | 9 | 291.413 | 324.242 | 10498.7 | 10498.7 | ...de stratigraphies = default; ...de matériaux et couleurs = Ivoire clair; ...de matériaux et couleurs - 1 = Ivoire clair; ...de matériaux et couleurs - 2 = Ivoire clair
Enveloppe 591225 | Rez-de-Jardin | Enveloppe | 591225 | 366 | 9000 | 1977773087 | 1977773087 | 1 | 0 | 0923 | 02 | Rez-de-Jardin | no | rectangle | 50.0475 | 291.413 | -1.94511e-11 | 96.17 | 291.413 | 276.17 | HAUT Rez-de-Jardin (Rez-de-chaussée 1047) | 0.0128504 | <aucun> | Rez-de-Jardin (Rez-de-Jardin 15545) | <aucun> | 50 | 50 | 291.4 | 291.4 | 500 | 500 | 500 | 14600 | 130000 | Ivoire clair | Ivoire clair | 131260 | 131260 | 9 | 291.413 | 450.427 | 14584.5 | 14584.5 | ...de stratigraphies = default; ...de matériaux et couleurs = Ivoire clair; ...de matériaux et couleurs - 1 = Ivoire clair; ...de matériaux et couleurs - 2 = Ivoire clair
Enveloppe 591529 | Rez-de-Jardin | Enveloppe | 591529 | 366 | 9000 | 1977773087 | 1977773087 | 0 | 0 | 0924 | 02 | Rez-de-Jardin | no | rectangle | 43.3635 | 291.413 | -1.94511e-11 | 0.879995 | 291.413 | 180.88 | HAUT Rez-de-Jardin (Rez-de-chaussée 1047) | 0.0128504 | <aucun> | Rez-de-Jardin (Rez-de-Jardin 15545) | <aucun> | 43.4 | 43.4 | 291.4 | 291.4 | 400 | 400 | 400 | 12600 | 110000 | Ivoire clair | Ivoire clair | 113730 | 113730 | 9 | 291.413 | 390.271 | 12636.7 | 12636.7 | ...de stratigraphies = default; ...de matériaux et couleurs = Ivoire clair; ...de matériaux et couleurs - 1 = Ivoire clair; ...de matériaux et couleurs - 2 = Ivoire clair
Enveloppe 590772 | Rez-de-Jardin | Enveloppe | 590772 | 366 | 9000 | 1977773087 | 1977773087 | 0 | 0 | 0921 | 02 | Rez-de-Jardin | no | rectangle | 105.608 | 291.413 | -1.94511e-11 | 0.229145 | 291.413 | 180.229 | HAUT Rez-de-Jardin (Rez-de-chaussée 1047) | 0.0128504 | <aucun> | Rez-de-Jardin (Rez-de-Jardin 15545) | <aucun> | 105.6 | 105.6 | 291.4 | 291.4 | 1000 | 1000 | 1000 | 30800 | 280000 | Ivoire clair | Ivoire clair | 276979 | 276979 | 9 | 291.413 | 950.469 | 30775.5 | 30775.5 | ...de stratigraphies = default; ...de matériaux et couleurs = Ivoire clair; ...de matériaux et couleurs - 1 = Ivoire clair; ...de matériaux et couleurs - 2 = Ivoire clair
Enveloppe 590863 | Rez-de-Jardin | Enveloppe | 590863 | 366 | 9000 | 1977773087 | 1977773087 | 1 | 0 | 0922 | 02 | Rez-de-Jardin | no | rectangle | 50.253 | 291.413 | -1.94511e-11 | 95.5821 | 291.413 | 275.582 | HAUT Rez-de-Jardin (Rez-de-chaussée 1047) | 0.0128504 | <aucun> | Rez-de-Jardin (Rez-de-Jardin 15545) | <aucun> | 50.3 | 50.3 | 291.4 | 291.4 | 500 | 500 | 500 | 14700 | 130000 | Ivoire clair | Ivoire clair | 131799 | 131799 | 9 | 291.413 | 452.277 | 14644.4 | 14644.4 | ...de stratigraphies = default; ...de matériaux et couleurs = Ivoire clair; ...de matériaux et couleurs - 1 = Ivoire clair; ...de matériaux et couleurs - 2 = Ivoire clair
Enveloppe 585409 | Rez-de-Jardin | Enveloppe | 585409 | 366 | 9000 | 1977773087 | 1977773087 | 1 | 0 | 0909 | 02 | Rez-de-Jardin | yes | rectangle | 27.6479 | 291.413 | -1.94511e-11 | 139.786 | 291.413 | 319.786 | HAUT Rez-de-Jardin (Rez-de-chaussée 1047) | 0.0128504 | <aucun> | Rez-de-Jardin (Rez-de-Jardin 15545) | <aucun> | 27.6 | 27.6 | 291.4 | 291.4 | 200 | 200 | 200 | 8000 | 70000 | Ivoire clair | Ivoire clair | 72512.6 | 72512.6 | 9 | 291.413 | 248.831 | 8056.95 | 8056.95 | ...de stratigraphies = default; ...de matériaux et couleurs = Ivoire clair; ...de matériaux et couleurs - 1 = Ivoire clair; ...de matériaux et couleurs - 2 = Ivoire clair
Enveloppe 585672 | Rez-de-Jardin | Enveloppe | 585672 | 366 | 9000 | 1977773087 | 1977773087 | 0 | 0 | 0910 | 02 | Rez-de-Jardin | yes | rectangle | 35.3669 | 291.413 | -1.94511e-11 | 45.9279 | 291.413 | 225.928 | HAUT Rez-de-Jardin (Rez-de-chaussée 1047) | 0.0128504 | <aucun> | Rez-de-Jardin (Rez-de-Jardin 15545) | <aucun> | 35.4 | 35.4 | 291.4 | 291.4 | 300 | 300 | 300 | 10300 | 90000 | Ivoire clair | Ivoire clair | 92757.5 | 92757.5 | 9 | 291.413 | 318.302 | 10306.4 | 10306.4 | ...de stratigraphies = default; ...de matériaux et couleurs = Ivoire clair; ...de matériaux et couleurs - 1 = Ivoire clair; ...de matériaux et couleurs - 2 = Ivoire clair
Enveloppe 585148 | Rez-de-Jardin | Enveloppe | 585148 | 366 | 9000 | 1977773087 | 1977773087 | 0 | 0 | 0907 | 02 | Rez-de-Jardin | yes | rectangle | 50.8941 | 291.413 | -1.94511e-11 | 132.776 | 291.413 | 312.776 | HAUT Rez-de-Jardin (Rez-de-chaussée 1047) | 0.0128504 | <aucun> | Rez-de-Jardin (Rez-de-Jardin 15545) | <aucun> | 50.9 | 50.9 | 291.4 | 291.4 | 500 | 500 | 500 | 14800 | 130000 | Ivoire clair | Ivoire clair | 133481 | 133481 | 9 | 291.413 | 458.047 | 14831.2 | 14831.2 | ...de stratigraphies = default; ...de matériaux et couleurs = Ivoire clair; ...de matériaux et couleurs - 1 = Ivoire clair; ...de matériaux et couleurs - 2 = Ivoire clair
Enveloppe 585149 | Rez-de-Jardin | Enveloppe | 585149 | 366 | 9000 | 1977773087 | 1977773087 | 1 | 0 | 0908 | 02 | Rez-de-Jardin | yes | rectangle | 111.794 | 291.413 | -1.94511e-11 | 45.936 | 291.413 | 225.936 | HAUT Rez-de-Jardin (Rez-de-chaussée 1047) | 0.0128504 | <aucun> | Rez-de-Jardin (Rez-de-Jardin 15545) | <aucun> | 111.8 | 111.8 | 291.4 | 291.4 | 1000 | 1000 | 1000 | 32600 | 290000 | Ivoire clair | Ivoire clair | 293205 | 193464 | 9 | 291.413 | 1006.15 | 32578.3 | 21429.7 | ...de stratigraphies = default; ...de matériaux et couleurs = Ivoire clair; ...de matériaux et couleurs - 1 = Ivoire clair; ...de matériaux et couleurs - 2 = Ivoire clair
Enveloppe 585673 | Rez-de-Jardin | Enveloppe | 585673 | 366 | 9000 | 1977773087 | 1977773087 | 1 | 0 | 0911 | 02 | Rez-de-Jardin | yes | rectangle | 23.4309 | 291.413 | -1.94511e-11 | 138.074 | 291.413 | 318.074 | HAUT Rez-de-Jardin (Rez-de-chaussée 1047) | 0.0128504 | <aucun> | Rez-de-Jardin (Rez-de-Jardin 15545) | <aucun> | 23.4 | 23.4 | 291.4 | 291.4 | 200 | 200 | 200 | 6800 | 60000 | Ivoire clair | Ivoire clair | 61452.5 | 61452.5 | 9 | 291.413 | 210.878 | 6828.06 | 6828.06 | ...de stratigraphies = default; ...de matériaux et couleurs = Ivoire clair; ...de matériaux et couleurs - 1 = Ivoire clair; ...de matériaux et couleurs - 2 = Ivoire clair
Enveloppe 588366 | Rez-de-Jardin | Enveloppe | 588366 | 366 | 9000 | 1977773087 | 1977773087 | 0 | 1 | 0914 | 02 | Rez-de-Jardin | no | rectangle | 114.016 | 291.413 | -1.94511e-11 | 0.294359 | 291.413 | 180.294 | HAUT Rez-de-Jardin (Rez-de-chaussée 1047) | 0.0128504 | <aucun> | Rez-de-Jardin (Rez-de-Jardin 15545) | <aucun> | 114 | 114 | 291.4 | 291.4 | 1000 | 1000 | 1000 | 33200 | 300000 | Ivoire clair | Ivoire clair | 299032 | 197919 | 9 | 291.413 | 1026.14 | 33225.8 | 21991.1 | ...de stratigraphies = default; ...de matériaux et couleurs = Ivoire clair; ...de matériaux et couleurs - 1 = Ivoire clair; ...de matériaux et couleurs - 2 = Ivoire clair
Enveloppe 588678 | Rez-de-Jardin | Enveloppe | 588678 | 366 | 9000 | 1977773087 | 1977773087 | 1 | 1 | 0915 | 02 | Rez-de-Jardin | no | rectangle | 259.533 | 291.413 | -1.94511e-11 | 0.293174 | 291.413 | 180.293 | HAUT Rez-de-Jardin (Rez-de-chaussée 1047) | 0.0128504 | <aucun> | Rez-de-Jardin (Rez-de-Jardin 15545) | <aucun> | 259.5 | 259.5 | 291.4 | 291.4 | 2300 | 2300 | 2300 | 75600 | 680000 | Ivoire clair | Ivoire clair | 680681 | 680681 | 9 | 291.413 | 2335.79 | 75631.2 | 75631.2 | ...de stratigraphies = default; ...de matériaux et couleurs = Ivoire clair; ...de matériaux et couleurs - 1 = Ivoire clair; ...de matériaux et couleurs - 2 = Ivoire clair
Enveloppe 587913 | Rez-de-Jardin | Enveloppe | 587913 | 366 | 9000 | 1977773087 | 1977773087 | 0 | 0 | 0912 | 02 | Rez-de-Jardin | no | rectangle | 23.3004 | 291.413 | -1.94511e-11 | 90.2312 | 291.413 | 270.231 | HAUT Rez-de-Jardin (Rez-de-chaussée 1047) | 0.0128504 | <aucun> | Rez-de-Jardin (Rez-de-Jardin 15545) | <aucun> | 23.3 | 23.3 | 291.4 | 291.4 | 200 | 200 | 200 | 6800 | 60000 | Ivoire clair | Ivoire clair | 61110.5 | 61110.5 | 9 | 291.413 | 209.704 | 6790.05 | 6790.05 | ...de stratigraphies = default; ...de matériaux et couleurs = Ivoire clair; ...de matériaux et couleurs - 1 = Ivoire clair; ...de matériaux et couleurs - 2 = Ivoire clair
Enveloppe 588365 | Rez-de-Jardin | Enveloppe | 588365 | 366 | 9000 | 1977773087 | 1977773087 | 0 | 1 | 0913 | 02 | Rez-de-Jardin | no | rectangle | 45.0809 | 291.413 | -1.94511e-11 | 93.7276 | 291.413 | 273.728 | HAUT Rez-de-Jardin (Rez-de-chaussée 1047) | 0.0128504 | <aucun> | Rez-de-Jardin (Rez-de-Jardin 15545) | <aucun> | 45.1 | 45.1 | 291.4 | 291.4 | 400 | 400 | 400 | 13100 | 120000 | Ivoire clair | Ivoire clair | 118235 | 118235 | 9 | 291.413 | 405.728 | 13137.2 | 13137.2 | ...de stratigraphies = default; ...de matériaux et couleurs = Ivoire clair; ...de matériaux et couleurs - 1 = Ivoire clair; ...de matériaux et couleurs - 2 = Ivoire clair
Enveloppe 71423 | Rez-de-Jardin | Enveloppe | 71423 | 366 | 9000 | 1977773087 | 1977773087 | 0 | 0 | 0151 | 02 | Rez-de-Jardin | yes | rectangle | 191.778 | 291.413 | -1.94511e-11 | 0.561191 | 291.413 | 180.561 | HAUT Rez-de-Jardin (Rez-de-chaussée 1047) | 0.0128504 | <aucun> | Rez-de-Jardin (Rez-de-Jardin 15545) | <aucun> | 191.8 | 191.8 | 291.4 | 291.4 | 1700 | 1700 | 1700 | 55900 | 500000 | Ivoire clair | Ivoire clair | 502979 | 502979 | 9 | 291.413 | 1726 | 55886.5 | 55886.5 | ...de stratigraphies = default; ...de matériaux et couleurs = Ivoire clair; ...de matériaux et couleurs - 1 = Ivoire clair; ...de matériaux et couleurs - 2 = Ivoire clair
Enveloppe 71409 | Rez-de-Jardin | Enveloppe | 71409 | 366 | 9000 | 1977773087 | 1977773087 | 1 | 0 | 0150 | 02 | Rez-de-Jardin | yes | rectangle | 184.827 | 291.413 | -1.94511e-11 | 90.6157 | 291.413 | 270.616 | HAUT Rez-de-Jardin (Rez-de-chaussée 1047) | 0.0128504 | <aucun> | Rez-de-Jardin (Rez-de-Jardin 15545) | <aucun> | 184.8 | 184.8 | 291.4 | 291.4 | 1700 | 1700 | 1700 | 53900 | 490000 | Ivoire clair | Ivoire clair | 484749 | 484749 | 9 | 291.413 | 1663.44 | 53861 | 53861 | ...de stratigraphies = default; ...de matériaux et couleurs = Ivoire clair; ...de matériaux et couleurs - 1 = Ivoire clair; ...de matériaux et couleurs - 2 = Ivoire clair
Enveloppe 74047 | Rez-de-Jardin | Enveloppe | 74047 | 366 | 9000 | 1977773087 | 1977773087 | 0 | 1 | 0170 | 02 | Rez-de-Jardin | no | rectangle | 108.131 | 291.413 | -1.94511e-11 | 89.994 | 291.413 | 269.994 | HAUT Rez-de-Jardin (Rez-de-chaussée 1047) | 0.0128504 | <aucun> | Rez-de-Jardin (Rez-de-Jardin 15545) | <aucun> | 108.1 | 108.1 | 291.4 | 291.4 | 1000 | 1000 | 1000 | 31500 | 280000 | Ivoire clair | Ivoire clair | 283596 | 283596 | 9 | 291.413 | 973.175 | 31510.7 | 31510.7 | ...de stratigraphies = default; ...de matériaux et couleurs = Ivoire clair; ...de matériaux et couleurs - 1 = Ivoire clair; ...de matériaux et couleurs - 2 = Ivoire clair
Enveloppe 76446 | Rez-de-Jardin | Enveloppe | 76446 | 366 | 9000 | 1977773087 | 1977773087 | 0 | 1 | 0175 | 02 | Rez-de-Jardin | no | rectangle | 139.392 | 291.413 | -1.94511e-11 | 0.905984 | 291.413 | 180.906 | HAUT Rez-de-Jardin (Rez-de-chaussée 1047) | 0.0128504 | <aucun> | Rez-de-Jardin (Rez-de-Jardin 15545) | <aucun> | 139.4 | 139.4 | 291.4 | 291.4 | 1300 | 1300 | 1300 | 40600 | 370000 | Ivoire clair | Ivoire clair | 365587 | 137177 | 9 | 291.413 | 1254.53 | 40620.7 | 15241.9 | ...de stratigraphies = default; ...de matériaux et couleurs = Ivoire clair; ...de matériaux et couleurs - 1 = Ivoire clair; ...de matériaux et couleurs - 2 = Ivoire clair
Enveloppe 76172 | Rez-de-Jardin | Enveloppe | 76172 | 366 | 9000 | 1977773087 | 1977773087 | 0 | 1 | 0172 | 02 | Rez-de-Jardin | no | rectangle | 213.353 | 291.413 | -1.94511e-11 | 0.483804 | 291.413 | 180.484 | HAUT Rez-de-Jardin (Rez-de-chaussée 1047) | 0.0128504 | <aucun> | Rez-de-Jardin (Rez-de-Jardin 15545) | <aucun> | 213.4 | 213.4 | 291.4 | 291.4 | 1900 | 1900 | 1900 | 62200 | 560000 | Ivoire clair | Ivoire clair | 559564 | 559564 | 9 | 291.413 | 1920.17 | 62173.8 | 62173.8 | ...de stratigraphies = default; ...de matériaux et couleurs = Ivoire clair; ...de matériaux et couleurs - 1 = Ivoire clair; ...de matériaux et couleurs - 2 = Ivoire clair
Enveloppe 57838 | Rez-de-Jardin | Enveloppe | 57838 | 366 | 9000 | 1977773087 | 1977773087 | 1 | 1 | 0113 | 02 | Rez-de-Jardin | no | rectangle | 119.738 | 291.413 | -1.94511e-11 | 89.698 | 291.413 | 269.698 | HAUT Rez-de-Jardin (Rez-de-chaussée 1047) | 0.0128504 | <aucun> | Rez-de-Jardin (Rez-de-Jardin 15545) | <aucun> | 119.7 | 119.7 | 291.4 | 291.4 | 1100 | 1100 | 1100 | 34900 | 310000 | Ivoire clair | Ivoire clair | 314040 | 77919.1 | 9 | 291.413 | 1077.64 | 34893.3 | 8657.68 | ...de stratigraphies = default; ...de matériaux et couleurs = Ivoire clair; ...de matériaux et couleurs - 1 = Ivoire clair; ...de matériaux et couleurs - 2 = Ivoire clair
Enveloppe 64861 | Rez-de-Jardin | Enveloppe | 64861 | 366 | 9000 | 1977773087 | 1977773087 | 0 | 1 | 0116 | 02 | Rez-de-Jardin | no | rectangle | 385.132 | 271.4 | -1.94511e-11 | 0.221025 | 271.4 | 180.221 | HAUT Rez-de-Jardin (Rez-de-chaussée 1047) | -20 | <aucun> | Rez-de-Jardin (Rez-de-Jardin 15545) | <aucun> | 385.1 | 385.1 | 271.4 | 271.4 | 3500 | 3500 | 3500 | 104500 | 940000 | Ivoire clair | Ivoire clair | 940724 | 840963 | 9 | 271.4 | 3466.19 | 104525 | 93440.3 | ...de stratigraphies = default; ...de matériaux et couleurs = Ivoire clair; ...de matériaux et couleurs - 1 = Ivoire clair; ...de matériaux et couleurs - 2 = Ivoire clair
Enveloppe 64871 | Rez-de-Jardin | Enveloppe | 64871 | 366 | 9000 | 1977773087 | 1977773087 | 1 | 1 | 0117 | 02 | Rez-de-Jardin | no | rectangle | 341.451 | 271.4 | -1.94511e-11 | 179.857 | 271.4 | 359.857 | HAUT Rez-de-Jardin (Rez-de-chaussée 1047) | -20 | <aucun> | Rez-de-Jardin (Rez-de-Jardin 15545) | <aucun> | 341.5 | 341.5 | 271.4 | 271.4 | 3100 | 3100 | 3100 | 92700 | 830000 | Ivoire clair | Ivoire clair | 834030 | 733372 | 9 | 271.4 | 3073.06 | 92670 | 81485.8 | ...de stratigraphies = default; ...de matériaux et couleurs = Ivoire clair; ...de matériaux et couleurs - 1 = Ivoire clair; ...de matériaux et couleurs - 2 = Ivoire clair
Enveloppe 69545 | Rez-de-Jardin | Enveloppe | 69545 | 366 | 9000 | 1977773087 | 1977773087 | 1 | 1 | 0132 | 02 | Rez-de-Jardin | no | rectangle | 23.958 | 281.4 | -1.94511e-11 | 90.1535 | 281.4 | 270.153 | HAUT Rez-de-Jardin (Rez-de-chaussée 1047) | -10 | <aucun> | Rez-de-Jardin (Rez-de-Jardin 15545) | <aucun> | 24 | 24 | 281.4 | 281.4 | 200 | 200 | 200 | 6800 | 60000 | Ivoire clair | Ivoire clair | 60676.1 | 60676.1 | 9 | 281.4 | 215.622 | 6741.79 | 6741.79 | ...de stratigraphies = default; ...de matériaux et couleurs = Ivoire clair; ...de matériaux et couleurs - 1 = Ivoire clair; ...de matériaux et couleurs - 2 = Ivoire clair
Enveloppe 52993 | Rez-de-Jardin | Enveloppe | 52993 | 366 | 9000 | 1977773087 | 1977773087 | 0 | 0 | 0080 | 02 | Rez-de-Jardin | no | rectangle | 150.277 | 291.413 | -1.94511e-11 | 90.6017 | 291.413 | 270.602 | HAUT Rez-de-Jardin (Rez-de-chaussée 1047) | 0.0128504 | <aucun> | Rez-de-Jardin (Rez-de-Jardin 15545) | <aucun> | 150.3 | 150.3 | 291.4 | 291.4 | 1400 | 1400 | 1400 | 43800 | 390000 | Ivoire clair | Ivoire clair | 394135 | 394135 | 9 | 291.413 | 1352.5 | 43792.8 | 43792.8 | ...de stratigraphies = default; ...de matériaux et couleurs = Ivoire clair; ...de matériaux et couleurs - 1 = Ivoire clair; ...de matériaux et couleurs - 2 = Ivoire clair
Enveloppe 55753 | Rez-de-Jardin | Enveloppe | 55753 | 366 | 9000 | 1977773087 | 1977773087 | 1 | 1 | 0104 | 02 | Rez-de-Jardin | no | rectangle | 143.536 | 291.413 | -1.94511e-11 | 89.5003 | 291.413 | 269.5 | HAUT Rez-de-Jardin (Rez-de-chaussée 1047) | 0.0128504 | <aucun> | Rez-de-Jardin (Rez-de-Jardin 15545) | <aucun> | 143.5 | 143.5 | 291.4 | 291.4 | 1300 | 1300 | 1300 | 41800 | 380000 | Ivoire clair | Ivoire clair | 376455 | 376455 | 9 | 291.413 | 1291.82 | 41828.3 | 41828.3 | ...de stratigraphies = default; ...de matériaux et couleurs = Ivoire clair; ...de matériaux et couleurs - 1 = Ivoire clair; ...de matériaux et couleurs - 2 = Ivoire clair
Enveloppe 57136 | Rez-de-Jardin | Enveloppe | 57136 | 366 | 9000 | 1977773087 | 1977773087 | 1 | 1 | 0109 | 02 | Rez-de-Jardin | no | rectangle | 254.919 | 291.413 | -1.94511e-11 | 0.052206 | 291.413 | 180.052 | HAUT Rez-de-Jardin (Rez-de-chaussée 1047) | 0.0128504 | <aucun> | Rez-de-Jardin (Rez-de-Jardin 15545) | <aucun> | 254.9 | 254.9 | 291.4 | 291.4 | 2300 | 2300 | 2300 | 74300 | 670000 | Ivoire clair | Ivoire clair | 668582 | 668582 | 9 | 291.413 | 2294.27 | 74286.9 | 74286.9 | ...de stratigraphies = default; ...de matériaux et couleurs = Ivoire clair; ...de matériaux et couleurs - 1 = Ivoire clair; ...de matériaux et couleurs - 2 = Ivoire clair
Enveloppe 57399 | Rez-de-Jardin | Enveloppe | 57399 | 366 | 9000 | 1977773087 | 1977773087 | 0 | 1 | 0110 | 02 | Rez-de-Jardin | no | rectangle | 188.541 | 291.413 | -1.94511e-11 | 91.2842 | 291.413 | 271.284 | HAUT Rez-de-Jardin (Rez-de-chaussée 1047) | 0.0128504 | <aucun> | Rez-de-Jardin (Rez-de-Jardin 15545) | <aucun> | 188.5 | 188.5 | 291.4 | 291.4 | 1700 | 1700 | 1700 | 54900 | 490000 | Ivoire clair | Ivoire clair | 494489 | 494489 | 9 | 291.413 | 1696.87 | 54943.3 | 54943.3 | ...de stratigraphies = default; ...de matériaux et couleurs = Ivoire clair; ...de matériaux et couleurs - 1 = Ivoire clair; ...de matériaux et couleurs - 2 = Ivoire clair
Enveloppe 55077 | Rez-de-Jardin | Enveloppe | 55077 | 366 | 9000 | 1977773087 | 1977773087 | 0 | 1 | 0100 | 02 | Rez-de-Jardin | no | rectangle | 192.283 | 291.413 | -1.94511e-11 | 0.313787 | 291.413 | 180.314 | HAUT Rez-de-Jardin (Rez-de-chaussée 1047) | 0.0128504 | <aucun> | Rez-de-Jardin (Rez-de-Jardin 15545) | <aucun> | 192.3 | 192.3 | 291.4 | 291.4 | 1700 | 1700 | 1700 | 56000 | 500000 | Ivoire clair | Ivoire clair | 504305 | 406998 | 9 | 291.413 | 1730.55 | 56033.9 | 45222 | ...de stratigraphies = default; ...de matériaux et couleurs = Ivoire clair; ...de matériaux et couleurs - 1 = Ivoire clair; ...de matériaux et couleurs - 2 = Ivoire clair
Enveloppe 229219 | Rez-de-Jardin | Enveloppe | 229219 | 366 | 9000 | 1977773087 | 1977773087 | 0 | 1 | 0513 | 02 | Rez-de-Jardin | no | rectangle | 100.604 | 291.413 | -1.94511e-11 | 179.471 | 291.413 | 359.471 | HAUT Rez-de-Jardin (Rez-de-chaussée 1047) | 0.0128504 | <aucun> | Rez-de-Jardin (Rez-de-Jardin 15545) | <aucun> | 100.6 | 100.6 | 291.4 | 291.4 | 900 | 900 | 900 | 29300 | 260000 | Ivoire clair | Ivoire clair | 263856 | 56806.6 | 9 | 291.413 | 905.437 | 29317.4 | 6311.85 | ...de stratigraphies = default; ...de matériaux et couleurs = Ivoire clair; ...de matériaux et couleurs - 1 = Ivoire clair; ...de matériaux et couleurs - 2 = Ivoire clair
Enveloppe 229400 | Rez-de-Jardin | Enveloppe | 229400 | 366 | 9000 | 1977773087 | 1977773087 | 1 | 1 | 0516 | 02 | Rez-de-Jardin | no | rectangle | 22.611 | 281.4 | -1.94511e-11 | 87.6044 | 281.4 | 267.604 | HAUT Rez-de-Jardin (Rez-de-chaussée 1047) | -10 | <aucun> | Rez-de-Jardin (Rez-de-Jardin 15545) | <aucun> | 22.6 | 22.6 | 281.4 | 281.4 | 200 | 200 | 200 | 6400 | 60000 | Ivoire clair | Ivoire clair | 57264.8 | 57264.8 | 9 | 281.4 | 203.499 | 6362.75 | 6362.75 | ...de stratigraphies = default; ...de matériaux et couleurs = Ivoire clair; ...de matériaux et couleurs - 1 = Ivoire clair; ...de matériaux et couleurs - 2 = Ivoire clair
Enveloppe 229437 | Rez-de-Jardin | Enveloppe | 229437 | 366 | 9000 | 1977773087 | 1977773087 | 0 | 1 | 0517 | 02 | Rez-de-Jardin | no | rectangle | 116.551 | 291.413 | -1.94511e-11 | 179.772 | 291.413 | 359.772 | HAUT Rez-de-Jardin (Rez-de-chaussée 1047) | 0.0128504 | <aucun> | Rez-de-Jardin (Rez-de-Jardin 15545) | <aucun> | 116.6 | 116.6 | 291.4 | 291.4 | 1000 | 1000 | 1000 | 34000 | 310000 | Ivoire clair | Ivoire clair | 305681 | 102515 | 9 | 291.413 | 1048.96 | 33964.6 | 11390.5 | ...de stratigraphies = default; ...de matériaux et couleurs = Ivoire clair; ...de matériaux et couleurs - 1 = Ivoire clair; ...de matériaux et couleurs - 2 = Ivoire clair
Enveloppe 229326 | Rez-de-Jardin | Enveloppe | 229326 | 366 | 9000 | 1977773087 | 1977773087 | 0 | 1 | 0514 | 02 | Rez-de-Jardin | no | rectangle | 21.0297 | 281.4 | -1.94511e-11 | 87.4016 | 281.4 | 267.402 | HAUT Rez-de-Jardin (Rez-de-chaussée 1047) | -10 | <aucun> | Rez-de-Jardin (Rez-de-Jardin 15545) | <aucun> | 21 | 21 | 281.4 | 281.4 | 200 | 200 | 200 | 5900 | 50000 | Ivoire clair | Ivoire clair | 53259.8 | 53259.8 | 9 | 281.4 | 189.267 | 5917.75 | 5917.75 | ...de stratigraphies = default; ...de matériaux et couleurs = Ivoire clair; ...de matériaux et couleurs - 1 = Ivoire clair; ...de matériaux et couleurs - 2 = Ivoire clair
Enveloppe 229363 | Rez-de-Jardin | Enveloppe | 229363 | 366 | 9000 | 1552655706 | 1552655706 | 0 | 1 | 0515 | 02 | Rez-de-Jardin | no | rectangle | 50.076 | 281.4 | -1.94511e-11 | 177.344 | 281.4 | 357.344 | HAUT Rez-de-Jardin (Rez-de-chaussée 1047) | -10 | <aucun> | Rez-de-Jardin (Rez-de-Jardin 15545) | <aucun> | 50.1 | 50.1 | 281.4 | 281.4 | 500 | 500 | 500 | 14100 | 130000 | 18 Travertin romain | 18 Travertin romain | 126823 | 126823 | 9 | 281.4 | 450.684 | 14091.4 | 14091.4 | ...de stratigraphies = default; ...de matériaux et couleurs = 18 Travertin romain; ...de matériaux et couleurs - 1 = 18 Travertin romain; ...de matériaux et couleurs - 2 = 18 Travertin romain
Enveloppe 229564 | Rez-de-Jardin | Enveloppe | 229564 | 366 | 9000 | 1977773087 | 1977773087 | 0 | 1 | 0518 | 02 | Rez-de-Jardin | no | rectangle | 21.1624 | 281.4 | -1.94511e-11 | 90.4337 | 281.4 | 270.434 | HAUT Rez-de-Jardin (Rez-de-chaussée 1047) | -10 | <aucun> | Rez-de-Jardin (Rez-de-Jardin 15545) | <aucun> | 21.2 | 21.2 | 281.4 | 281.4 | 200 | 200 | 200 | 6000 | 50000 | Ivoire clair | Ivoire clair | 53595.9 | 53595.9 | 9 | 281.4 | 190.461 | 5955.1 | 5955.1 | ...de stratigraphies = default; ...de matériaux et couleurs = Ivoire clair; ...de matériaux et couleurs - 1 = Ivoire clair; ...de matériaux et couleurs - 2 = Ivoire clair
Enveloppe 351530 | Rez-de-Jardin | Enveloppe | 351530 | 366 | 9000 | 1552655706 | 1552655706 | 0 | 1 | 0567 | 02 | Rez-de-Jardin | no | rectangle | 230.357 | 291.413 | -1.94511e-11 | 179.754 | 291.413 | 359.754 | HAUT Rez-de-Jardin (Rez-de-chaussée 1047) | 0.0128504 | <aucun> | Rez-de-Jardin (Rez-de-Jardin 15545) | <aucun> | 230.4 | 230.4 | 291.4 | 291.4 | 2100 | 2100 | 2100 | 67100 | 600000 | 18 Travertin romain | 18 Travertin romain | 604161 | 504746 | 9 | 291.413 | 2073.21 | 67129 | 56082.8 | ...de stratigraphies = default; ...de matériaux et couleurs = 18 Travertin romain; ...de matériaux et couleurs - 1 = 18 Travertin romain; ...de matériaux et couleurs - 2 = 18 Travertin romain
Enveloppe 352362 | Rez-de-Jardin | Enveloppe | 352362 | 366 | 9000 | 1552655706 | 1552655706 | 0 | 1 | 0568 | 02 | Rez-de-Jardin | no | rectangle | 228.062 | 281.4 | -1.94511e-11 | 179.993 | 281.4 | 359.993 | HAUT Rez-de-Jardin (Rez-de-chaussée 1047) | -10 | <aucun> | Rez-de-Jardin (Rez-de-Jardin 15545) | <aucun> | 228.1 | 228.1 | 281.4 | 281.4 | 2100 | 2100 | 2100 | 64200 | 580000 | 18 Travertin romain | 18 Travertin romain | 577591 | 478188 | 9 | 281.4 | 2052.56 | 64176.8 | 53132 | ...de stratigraphies = default; ...de matériaux et couleurs = 18 Travertin romain; ...de matériaux et couleurs - 1 = 18 Travertin romain; ...de matériaux et couleurs - 2 = 18 Travertin romain
Enveloppe 351360 | Rez-de-Jardin | Enveloppe | 351360 | 366 | 9000 | 1552655706 | 1552655706 | 1 | 1 | 0565 | 02 | Rez-de-Jardin | no | rectangle | 257.025 | 291.413 | -1.94511e-11 | 0.081221 | 291.413 | 180.081 | HAUT Rez-de-Jardin (Rez-de-chaussée 1047) | 0.0128504 | <aucun> | Rez-de-Jardin (Rez-de-Jardin 15545) | <aucun> | 257 | 257 | 291.4 | 291.4 | 2300 | 2300 | 2300 | 74900 | 670000 | 18 Travertin romain | 18 Travertin romain | 674105 | 674105 | 9 | 291.413 | 2313.23 | 74900.5 | 74900.5 | ...de stratigraphies = default; ...de matériaux et couleurs = 18 Travertin romain; ...de matériaux et couleurs - 1 = 18 Travertin romain; ...de matériaux et couleurs - 2 = 18 Travertin romain
Enveloppe 351445 | Rez-de-Jardin | Enveloppe | 351445 | 366 | 9000 | 1552655706 | 1552655706 | 1 | 1 | 0566 | 02 | Rez-de-Jardin | no | rectangle | 246.263 | 291.413 | -1.94511e-11 | 44.9617 | 291.413 | 224.962 | HAUT Rez-de-Jardin (Rez-de-chaussée 1047) | 0.0128504 | <aucun> | Rez-de-Jardin (Rez-de-Jardin 15545) | <aucun> | 246.3 | 246.3 | 291.4 | 291.4 | 2200 | 2200 | 2200 | 71800 | 650000 | 18 Travertin romain | 18 Travertin romain | 645879 | 546042 | 9 | 291.413 | 2216.37 | 71764.3 | 60671.3 | ...de stratigraphies = default; ...de matériaux et couleurs = 18 Travertin romain; ...de matériaux et couleurs - 1 = 18 Travertin romain; ...de matériaux et couleurs - 2 = 18 Travertin romain
Enveloppe 354991 | Rez-de-Jardin | Enveloppe | 354991 | 366 | 9000 | 1552655706 | 1552655706 | 1 | 1 | 0572 | 02 | Rez-de-Jardin | no | rectangle | 253.872 | 291.413 | -1.94511e-11 | 89.71 | 291.413 | 269.71 | HAUT Rez-de-Jardin (Rez-de-chaussée 1047) | 0.0128504 | <aucun> | Rez-de-Jardin (Rez-de-Jardin 15545) | <aucun> | 253.9 | 253.9 | 291.4 | 291.4 | 2300 | 2300 | 2300 | 74000 | 670000 | 18 Travertin romain | 18 Travertin romain | 665834 | 665834 | 9 | 291.413 | 2284.84 | 73981.5 | 73981.5 | ...de stratigraphies = default; ...de matériaux et couleurs = 18 Travertin romain; ...de matériaux et couleurs - 1 = 18 Travertin romain; ...de matériaux et couleurs - 2 = 18 Travertin romain
Enveloppe 354607 | Rez-de-Jardin | Enveloppe | 354607 | 366 | 9000 | 1552655706 | 1552655706 | 1 | 1 | 0571 | 02 | Rez-de-Jardin | no | rectangle | 366.339 | 291.413 | -1.94511e-11 | 89.9643 | 291.413 | 269.964 | HAUT Rez-de-Jardin (Rez-de-chaussée 1047) | 0.0128504 | <aucun> | Rez-de-Jardin (Rez-de-Jardin 15545) | <aucun> | 366.3 | 366.3 | 291.4 | 291.4 | 3300 | 3300 | 3300 | 106700 | 960000 | 18 Travertin romain | 18 Travertin romain | 960804 | 726187 | 9 | 291.413 | 3297.05 | 106756 | 80687.4 | ...de stratigraphies = default; ...de matériaux et couleurs = 18 Travertin romain; ...de matériaux et couleurs - 1 = 18 Travertin romain; ...de matériaux et couleurs - 2 = 18 Travertin romain
Enveloppe 351190 | Rez-de-Jardin | Enveloppe | 351190 | 366 | 9000 | 1552655706 | 1552655706 | 0 | 1 | 0563 | 02 | Rez-de-Jardin | no | rectangle | 257.001 | 291.413 | -1.94511e-11 | 89.8114 | 291.413 | 269.811 | HAUT Rez-de-Jardin (Rez-de-chaussée 1047) | 0.0128504 | <aucun> | Rez-de-Jardin (Rez-de-Jardin 15545) | <aucun> | 257 | 257 | 291.4 | 291.4 | 2300 | 2300 | 2300 | 74900 | 670000 | 18 Travertin romain | 18 Travertin romain | 674041 | 674041 | 9 | 291.413 | 2313.01 | 74893.4 | 74893.4 | ...de stratigraphies = default; ...de matériaux et couleurs = 18 Travertin romain; ...de matériaux et couleurs - 1 = 18 Travertin romain; ...de matériaux et couleurs - 2 = 18 Travertin romain
Enveloppe 351275 | Rez-de-Jardin | Enveloppe | 351275 | 366 | 9000 | 1552655706 | 1552655706 | 0 | 1 | 0564 | 02 | Rez-de-Jardin | no | rectangle | 258.01 | 291.413 | -1.94511e-11 | 134.993 | 291.413 | 314.993 | HAUT Rez-de-Jardin (Rez-de-chaussée 1047) | 0.0128504 | <aucun> | Rez-de-Jardin (Rez-de-Jardin 15545) | <aucun> | 258 | 258 | 291.4 | 291.4 | 2300 | 2300 | 2300 | 75200 | 680000 | 18 Travertin romain | 18 Travertin romain | 676686 | 576739 | 9 | 291.413 | 2322.09 | 75187.4 | 64082.1 | ...de stratigraphies = default; ...de matériaux et couleurs = 18 Travertin romain; ...de matériaux et couleurs - 1 = 18 Travertin romain; ...de matériaux et couleurs - 2 = 18 Travertin romain
Enveloppe 351105 | Rez-de-Jardin | Enveloppe | 351105 | 366 | 9000 | 1552655706 | 1977773087 | 0 | 1 | 0562 | 02 | Rez-de-Jardin | no | rectangle | 112.017 | 291.413 | -1.94511e-11 | 44.432 | 291.413 | 224.432 | HAUT Rez-de-Jardin (Rez-de-chaussée 1047) | 0.0128504 | <aucun> | Rez-de-Jardin (Rez-de-Jardin 15545) | <aucun> | 112 | 112 | 291.4 | 291.4 | 1000 | 1000 | 1000 | 32600 | 290000 | 18 Travertin romain | Ivoire clair | 293790 | 293790 | 9 | 291.413 | 1008.16 | 32643.3 | 32643.3 | ...de stratigraphies = default; ...de matériaux et couleurs - 1 = Ivoire clair; ...de matériaux et couleurs - 2 = Ivoire clair; ...de matériaux et couleurs = 18 Travertin romain
Enveloppe 362015 | Rez-de-Jardin | Enveloppe | 362015 | 366 | 9000 | 1977773087 | 1977773087 | 0 | 1 | 0576 | 02 | Rez-de-Jardin | no | rectangle | 166.499 | 291.413 | -1.94511e-11 | 90.2334 | 291.413 | 270.233 | HAUT Rez-de-Jardin (Rez-de-chaussée 1047) | 0.0128504 | <aucun> | Rez-de-Jardin (Rez-de-Jardin 15545) | <aucun> | 166.5 | 166.5 | 291.4 | 291.4 | 1500 | 1500 | 1500 | 48500 | 440000 | Ivoire clair | Ivoire clair | 436680 | 436680 | 9 | 291.413 | 1498.49 | 48520 | 48520 | ...de stratigraphies = default; ...de matériaux et couleurs = Ivoire clair; ...de matériaux et couleurs - 1 = Ivoire clair; ...de matériaux et couleurs - 2 = Ivoire clair
Enveloppe 362187 | Rez-de-Jardin | Enveloppe | 362187 | 366 | 9000 | 1552655706 | 1552655706 | 1 | 1 | 0577 | 02 | Rez-de-Jardin | no | rectangle | 912.323 | 291.413 | -1.94511e-11 | 179.806 | 291.413 | 359.806 | HAUT Rez-de-Jardin (Rez-de-chaussée 1047) | 0.0128504 | <aucun> | Rez-de-Jardin (Rez-de-Jardin 15545) | <aucun> | 912.3 | 912.3 | 291.4 | 291.4 | 8200 | 8200 | 8200 | 265800 | 2390000 | 18 Travertin romain | 18 Travertin romain | 2392767 | 2191433 | 9 | 291.413 | 8210.91 | 265863 | 243493 | ...de stratigraphies = default; ...de matériaux et couleurs = 18 Travertin romain; ...de matériaux et couleurs - 1 = 18 Travertin romain; ...de matériaux et couleurs - 2 = 18 Travertin romain
Enveloppe 357221 | Rez-de-Jardin | Enveloppe | 357221 | 366 | 9000 | 1977773087 | 1977773087 | 1 | 1 | 0575 | 02 | Rez-de-Jardin | no | rectangle | 340.9 | 291.413 | -1.94511e-11 | 89.6611 | 291.413 | 269.661 | HAUT Rez-de-Jardin (Rez-de-chaussée 1047) | 0.0128504 | <aucun> | Rez-de-Jardin (Rez-de-Jardin 15545) | <aucun> | 340.9 | 340.9 | 291.4 | 291.4 | 3100 | 3100 | 3100 | 99300 | 890000 | Ivoire clair | Ivoire clair | 894084 | 177496 | 9 | 291.413 | 3068.1 | 99342.6 | 19721.8 | ...de stratigraphies = default; ...de matériaux et couleurs = Ivoire clair; ...de matériaux et couleurs - 1 = Ivoire clair; ...de matériaux et couleurs - 2 = Ivoire clair
Enveloppe 362512 | Rez-de-Jardin | Enveloppe | 362512 | 366 | 9000 | 1552655706 | 1552655706 | 0 | 1 | 0578 | 02 | Rez-de-Jardin | no | rectangle | 159.325 | 291.413 | -1.94511e-11 | 90.4214 | 291.413 | 270.421 | HAUT Rez-de-Jardin (Rez-de-chaussée 1047) | 0.0128504 | <aucun> | Rez-de-Jardin (Rez-de-Jardin 15545) | <aucun> | 159.3 | 159.3 | 291.4 | 291.4 | 1400 | 1400 | 1400 | 46400 | 420000 | 18 Travertin romain | 18 Travertin romain | 417865 | 417865 | 9 | 291.413 | 1433.93 | 46429.4 | 46429.4 | ...de stratigraphies = default; ...de matériaux et couleurs = 18 Travertin romain; ...de matériaux et couleurs - 1 = 18 Travertin romain; ...de matériaux et couleurs - 2 = 18 Travertin romain
Enveloppe 292554 | Rez-de-Jardin | Enveloppe | 292554 | 366 | 9000 | 1552655706 | 1552655706 | 0 | 1 | 0532 | 02 | Rez-de-Jardin | no | rectangle | 152.142 | 281.4 | -1.94511e-11 | 179.624 | 281.4 | 359.624 | HAUT Rez-de-Jardin (Rez-de-chaussée 1047) | -10 | <aucun> | Rez-de-Jardin (Rez-de-Jardin 15545) | <aucun> | 152.1 | 152.1 | 281.4 | 281.4 | 1400 | 1400 | 1400 | 42800 | 390000 | 18 Travertin romain | 18 Travertin romain | 385316 | 385316 | 9 | 281.4 | 1369.28 | 42812.9 | 42812.9 | ...de stratigraphies = default; ...de matériaux et couleurs = 18 Travertin romain; ...de matériaux et couleurs - 1 = 18 Travertin romain; ...de matériaux et couleurs - 2 = 18 Travertin romain
Enveloppe 229601 | Rez-de-Jardin | Enveloppe | 229601 | 366 | 9000 | 1552655706 | 1552655706 | 1 | 1 | 0519 | 02 | Rez-de-Jardin | no | rectangle | 210.345 | 281.4 | -1.94511e-11 | 0.0371683 | 281.4 | 180.037 | HAUT Rez-de-Jardin (Rez-de-chaussée 1047) | -10 | <aucun> | Rez-de-Jardin (Rez-de-Jardin 15545) | <aucun> | 210.3 | 210.3 | 281.4 | 281.4 | 1900 | 1900 | 1900 | 59200 | 530000 | 18 Travertin romain | 18 Travertin romain | 532720 | 532720 | 9 | 281.4 | 1893.1 | 59191.1 | 59191.1 | ...de stratigraphies = default; ...de matériaux et couleurs = 18 Travertin romain; ...de matériaux et couleurs - 1 = 18 Travertin romain; ...de matériaux et couleurs - 2 = 18 Travertin romain
Enveloppe 229684 | Rez-de-Jardin | Enveloppe | 229684 | 366 | 9000 | 1977773087 | 1977773087 | 1 | 1 | 0520 | 02 | Rez-de-Jardin | no | rectangle | 663.444 | 291.413 | -1.94511e-11 | 89.8322 | 291.413 | 269.832 | HAUT Rez-de-Jardin (Rez-de-chaussée 1047) | 0.0128504 | <aucun> | Rez-de-Jardin (Rez-de-Jardin 15545) | <aucun> | 663.4 | 663.4 | 291.4 | 291.4 | 6000 | 6000 | 6000 | 193300 | 1740000 | Ivoire clair | Ivoire clair | 1740026 | 1429409 | 9 | 291.413 | 5970.99 | 193336 | 158823 | ...de stratigraphies = default; ...de matériaux et couleurs = Ivoire clair; ...de matériaux et couleurs - 1 = Ivoire clair; ...de matériaux et couleurs - 2 = Ivoire clair
Enveloppe 238929 | Rez-de-Jardin | Enveloppe | 238929 | 366 | 9000 | 1977773087 | 1977773087 | 1 | 1 | 0524 | 02 | Rez-de-Jardin | no | rectangle | 171.672 | 391.4 | -1.94511e-11 | 1.27448 | 391.4 | 181.274 | HAUT Rez-de-Jardin (Rez-de-chaussée 1047) | 100 | <aucun> | Rez-de-Jardin (Rez-de-Jardin 15545) | <aucun> | 171.7 | 171.7 | 391.4 | 391.4 | 1500 | 1500 | 1500 | 67200 | 600000 | Ivoire clair | Ivoire clair | 604733 | 36343.4 | 9 | 391.4 | 1545.05 | 67192.6 | 4038.15 | ...de stratigraphies = default; ...de matériaux et couleurs = Ivoire clair; ...de matériaux et couleurs - 1 = Ivoire clair; ...de matériaux et couleurs - 2 = Ivoire clair
Enveloppe 238930 | Rez-de-Jardin | Enveloppe | 238930 | 366 | 9000 | 1552655706 | 1552655706 | 1 | 1 | 0525 | 02 | Rez-de-Jardin | no | rectangle | 177.744 | 281.4 | -1.94511e-11 | 89.8322 | 281.4 | 269.832 | HAUT Rez-de-Jardin (Rez-de-chaussée 1047) | -10 | <aucun> | Rez-de-Jardin (Rez-de-Jardin 15545) | <aucun> | 177.7 | 177.7 | 281.4 | 281.4 | 1600 | 1600 | 1600 | 50000 | 450000 | 18 Travertin romain | 18 Travertin romain | 450155 | 450155 | 9 | 281.4 | 1599.7 | 50017.2 | 50017.2 | ...de stratigraphies = default; ...de matériaux et couleurs = 18 Travertin romain; ...de matériaux et couleurs - 1 = 18 Travertin romain; ...de matériaux et couleurs - 2 = 18 Travertin romain
Enveloppe 315782 | Rez-de-Jardin | Enveloppe | 315782 | 366 | 9000 | 1977773087 | 1977773087 | 1 | 1 | 0553 | 02 | Rez-de-Jardin | no | rectangle | 28.6935 | 291.413 | -1.94511e-11 | 0.0692565 | 291.413 | 180.069 | HAUT Rez-de-Jardin (Rez-de-chaussée 1047) | 0.0128504 | <aucun> | Rez-de-Jardin (Rez-de-Jardin 15545) | <aucun> | 28.7 | 28.7 | 291.4 | 291.4 | 300 | 300 | 300 | 8400 | 80000 | Ivoire clair | Ivoire clair | 75255 | 75255 | 9 | 291.413 | 258.242 | 8361.67 | 8361.67 | ...de stratigraphies = default; ...de matériaux et couleurs = Ivoire clair; ...de matériaux et couleurs - 1 = Ivoire clair; ...de matériaux et couleurs - 2 = Ivoire clair
Enveloppe 315548 | Rez-de-Jardin | Enveloppe | 315548 | 366 | 9000 | 1977773087 | 1977773087 | 1 | 1 | 0552 | 02 | Rez-de-Jardin | no | rectangle | 26.8799 | 291.413 | -1.94511e-11 | 179.691 | 291.413 | 359.691 | HAUT Rez-de-Jardin (Rez-de-chaussée 1047) | 0.0128504 | <aucun> | Rez-de-Jardin (Rez-de-Jardin 15545) | <aucun> | 26.9 | 26.9 | 291.4 | 291.4 | 200 | 200 | 200 | 7800 | 70000 | Ivoire clair | Ivoire clair | 70498.5 | 70498.5 | 9 | 291.413 | 241.919 | 7833.17 | 7833.17 | ...de stratigraphies = default; ...de matériaux et couleurs = Ivoire clair; ...de matériaux et couleurs - 1 = Ivoire clair; ...de matériaux et couleurs - 2 = Ivoire clair
Enveloppe 310165 | Rez-de-Jardin | Enveloppe | 310165 | 366 | 9000 | 1552655706 | 1552655706 | 1 | 1 | 0539 | 02 | Rez-de-Jardin | no | rectangle | 150.215 | 291.413 | -1.94511e-11 | 89.8565 | 291.413 | 269.856 | HAUT Rez-de-Jardin (Rez-de-chaussée 1047) | 0.0128504 | <aucun> | Rez-de-Jardin (Rez-de-Jardin 15545) | <aucun> | 150.2 | 150.2 | 291.4 | 291.4 | 1400 | 1400 | 1400 | 43800 | 390000 | 18 Travertin romain | 18 Travertin romain | 393972 | 393972 | 9 | 291.413 | 1351.94 | 43774.6 | 43774.6 | ...de stratigraphies = default; ...de matériaux et couleurs = 18 Travertin romain; ...de matériaux et couleurs - 1 = 18 Travertin romain; ...de matériaux et couleurs - 2 = 18 Travertin romain
Enveloppe 310224 | Rez-de-Jardin | Enveloppe | 310224 | 366 | 9000 | 1552655706 | 1552655706 | 1 | 1 | 0540 | 02 | Rez-de-Jardin | no | rectangle | 621.01 | 291.413 | -1.94511e-11 | 179.862 | 291.413 | 359.862 | HAUT Rez-de-Jardin (Rez-de-chaussée 1047) | 0.0128504 | <aucun> | Rez-de-Jardin (Rez-de-Jardin 15545) | <aucun> | 621 | 621 | 291.4 | 291.4 | 5600 | 5600 | 5600 | 181000 | 1630000 | 18 Travertin romain | 18 Travertin romain | 1628734 | 1529447 | 9 | 291.413 | 5589.09 | 180970 | 169939 | ...de stratigraphies = default; ...de matériaux et couleurs = 18 Travertin romain; ...de matériaux et couleurs - 1 = 18 Travertin romain; ...de matériaux et couleurs - 2 = 18 Travertin romain
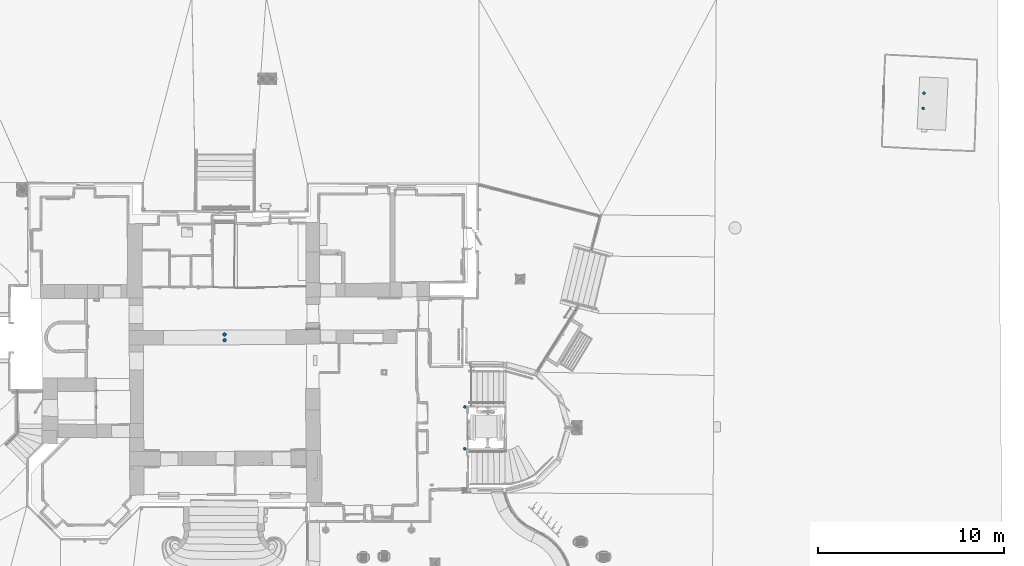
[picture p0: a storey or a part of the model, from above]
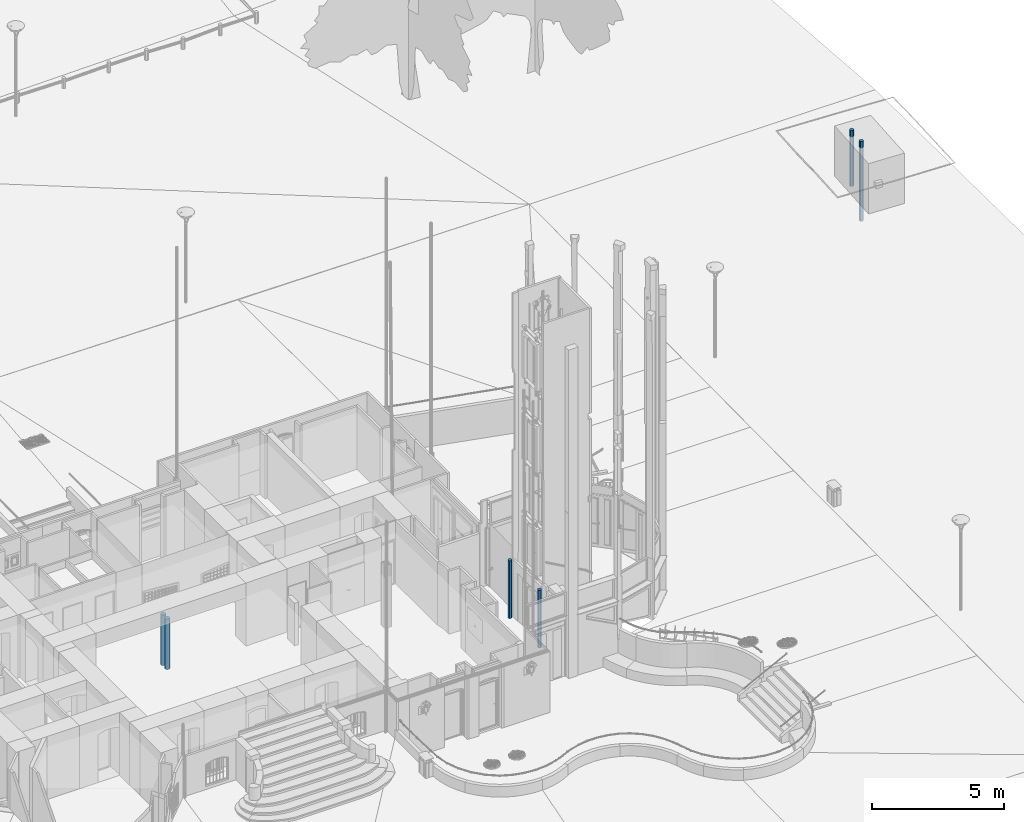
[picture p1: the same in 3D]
Properties of the parts of a building model (IFC2X3), part 30 of 37

# IfcWallStandardCase: default 90 (499)
Name | In | Description | __RECOGNIZE__, ID = IFC_Pset_Caractéristiques, ID | TPLG | TPLG_OD | 0, Crc | 1, Crc = 2, Crc | Alignment | ExternalFace | Numérotation | Numéro niveau | Titre niveau | Épaisseur VARIABLE | Forme en Élévation | Longueur (cm) = NominalLength (cm) | IFC_Pset_Géométrie, Hauteur (cm) = IFC_Pset_Géométrie_P1 (POINT initial), Hauteur (cm) | IFC_Pset_Géométrie, Cote (cm) = IFC_Pset_Géométrie_P1 (POINT initial), Cote (cm) = IFC_Pset_Géométrie_P2 (POINT final), Cote (cm) = IFC_Pset_Système de Référence Altimétrique_INFÉRIEUR, delta (cm) = IFC_Pset_Système de Référence Altimétrique_INFÉRIEUR, delta (P1) (cm) = IFC_Pset_Système de Référence Altimétrique_INFÉRIEUR, delta (P2) (cm) | IFC_Pset_Géométrie_P1 (POINT initial), Angle XY (deg) | IFC_Pset_Géométrie_P2 (POINT final), Hauteur (cm) | IFC_Pset_Géométrie_P2 (POINT final), Angle XY (deg) | IFC_Pset_Système de Référence Altimétrique_SUPÉRIEUR, NIVEAU | IFC_Pset_Système de Référence Altimétrique_SUPÉRIEUR, delta (cm) = IFC_Pset_Système de Référence Altimétrique_SUPÉRIEUR, delta (P1) (cm) = IFC_Pset_Système de Référence Altimétrique_SUPÉRIEUR, delta (P2) (cm) | IFC_Pset_Système de Référence Altimétrique_SUPÉRIEUR, sous Niveau | IFC_Pset_Système de Référence Altimétrique_INFÉRIEUR, NIVEAU | IFC_Pset_Système de Référence Altimétrique_INFÉRIEUR, sous Niveau | Longueur Pied (cm) | Longueur Tête (cm) | Hauteur Maximale (cm) | Hauteur Minimale (cm) | Surface en Plan (cm2) | Surface Pied (cm2) | Surface Tête (cm2) | Surface de la Paroi (cm2) | Volume (cm3) | Face gauche | Face droite = Face latérale | GrossVolume (cm3) | NetVolume (cm3) | NominalWidth (cm) | NominalHeight (cm) | GrossFootprintArea (cm2) = NetFootprintArea (cm2) | GrossSideArea (cm2) | NetSideArea (cm2) | Group
Enveloppe 310077 | Rez-de-Jardin | Enveloppe | 310077 | 366 | 9000 | 1552655706 | 1552655706 | 1 | 1 | 0538 | 02 | Rez-de-Jardin | no | rectangle | 289.064 | 291.413 | -1.94511e-11 | 179.931 | 291.413 | 359.931 | HAUT Rez-de-Jardin (Rez-de-chaussée 1047) | 0.0128504 | <aucun> | Rez-de-Jardin (Rez-de-Jardin 15545) | <aucun> | 289.1 | 289.1 | 291.4 | 291.4 | 2600 | 2600 | 2600 | 84200 | 760000 | 18 Travertin romain | 18 Travertin romain | 758134 | 699555 | 9 | 291.413 | 2601.58 | 84237.1 | 77728.3 | ...de stratigraphies = default; ...de matériaux et couleurs = 18 Travertin romain; ...de matériaux et couleurs - 1 = 18 Travertin romain; ...de matériaux et couleurs - 2 = 18 Travertin romain
Enveloppe 310283 | Rez-de-Jardin | Enveloppe | 310283 | 366 | 9000 | 1552655706 | 1552655706 | 0 | 1 | 0541 | 02 | Rez-de-Jardin | no | rectangle | 212.204 | 291.413 | -1.94511e-11 | 89.8195 | 291.413 | 269.819 | HAUT Rez-de-Jardin (Rez-de-chaussée 1047) | 0.0128504 | <aucun> | Rez-de-Jardin (Rez-de-Jardin 15545) | <aucun> | 212.2 | 212.2 | 291.4 | 291.4 | 1900 | 1900 | 1900 | 61800 | 560000 | 18 Travertin romain | 18 Travertin romain | 556552 | 556552 | 9 | 291.413 | 1909.84 | 61839.1 | 61839.1 | ...de stratigraphies = default; ...de matériaux et couleurs = 18 Travertin romain; ...de matériaux et couleurs - 1 = 18 Travertin romain; ...de matériaux et couleurs - 2 = 18 Travertin romain
Enveloppe 310342 | Rez-de-Jardin | Enveloppe | 310342 | 366 | 9000 | 1552655706 | 1552655706 | 0 | 1 | 0542 | 02 | Rez-de-Jardin | no | rectangle | 339.066 | 291.413 | -1.94511e-11 | 89.7205 | 291.413 | 269.72 | HAUT Rez-de-Jardin (Rez-de-chaussée 1047) | 0.0128504 | <aucun> | Rez-de-Jardin (Rez-de-Jardin 15545) | <aucun> | 339.1 | 339.1 | 291.4 | 291.4 | 3100 | 3100 | 3100 | 98800 | 890000 | 18 Travertin romain | 18 Travertin romain | 889275 | 789587 | 9 | 291.413 | 3051.59 | 98808.3 | 87731.9 | ...de stratigraphies = default; ...de matériaux et couleurs = 18 Travertin romain; ...de matériaux et couleurs - 1 = 18 Travertin romain; ...de matériaux et couleurs - 2 = 18 Travertin romain
Enveloppe 310401 | Rez-de-Jardin | Enveloppe | 310401 | 366 | 9000 | 1552655706 | 1552655706 | 1 | 1 | 0543 | 02 | Rez-de-Jardin | no | rectangle | 99.2652 | 291.413 | -1.94511e-11 | 179.458 | 291.413 | 359.458 | HAUT Rez-de-Jardin (Rez-de-chaussée 1047) | 0.0128504 | <aucun> | Rez-de-Jardin (Rez-de-Jardin 15545) | <aucun> | 99.3 | 99.3 | 291.4 | 291.4 | 900 | 900 | 900 | 28900 | 260000 | 18 Travertin romain | 18 Travertin romain | 260345 | 260345 | 9 | 291.413 | 893.387 | 28927.2 | 28927.2 | ...de stratigraphies = default; ...de matériaux et couleurs = 18 Travertin romain; ...de matériaux et couleurs - 1 = 18 Travertin romain; ...de matériaux et couleurs - 2 = 18 Travertin romain
Enveloppe 135077 | Rez-de-Jardin | Enveloppe | 135077 | 366 | 9000 | 1977773087 | 1977773087 | 1 | 0 | 0315 | 02 | Rez-de-Jardin | no | rectangle | 30.5392 | 441.4 | 0 | 179.627 | 441.4 | 359.627 | HAUT Rez-de-Jardin (Rez-de-chaussée 1047) | 100 | <aucun> | Rez-de-Jardin (Rez-de-Jardin 15545) | extérieur | 30.5 | 30.5 | 441.4 | 441.4 | 300 | 300 | 300 | 13500 | 120000 | Ivoire clair | Ivoire clair | 121320 | 121320 | 9 | 441.4 | 274.853 | 13480 | 13480 | ...de stratigraphies = default; ...de matériaux et couleurs = Ivoire clair; ...de matériaux et couleurs - 1 = Ivoire clair; ...de matériaux et couleurs - 2 = Ivoire clair
Enveloppe 76265 | Rez-de-Jardin | Enveloppe | 76265 | 366 | 9000 | 1552655706 | 1552655706 | 1 | 1 | 0173 | 02 | Rez-de-Jardin | no | rectangle | 593.758 | 291.413 | -1.94511e-11 | 179.86 | 291.413 | 359.86 | HAUT Rez-de-Jardin (Rez-de-chaussée 1047) | 0.0128504 | <aucun> | Rez-de-Jardin (Rez-de-Jardin 15545) | <aucun> | 593.8 | 593.8 | 291.4 | 291.4 | 5400 | 5400 | 5400 | 173000 | 1560000 | 18 Travertin romain | 18 Travertin romain | 1557261 | 1271455 | 9 | 291.413 | 5343.82 | 173029 | 141273 | ...de stratigraphies = default; ...de matériaux et couleurs = 18 Travertin romain; ...de matériaux et couleurs - 1 = 18 Travertin romain; ...de matériaux et couleurs - 2 = 18 Travertin romain
Enveloppe 53200 | Rez-de-Jardin | Enveloppe | 53200 | 366 | 9000 | 1977773087 | 1977773087 | 0 | 0 | 0088 | 02 | Rez-de-Jardin | no | rectangle | 397.88 | 291.413 | -1.94511e-11 | 90.6101 | 291.413 | 270.61 | HAUT Rez-de-Jardin (Rez-de-chaussée 1047) | 0.0128504 | <aucun> | Rez-de-Jardin (Rez-de-Jardin 15545) | <aucun> | 397.9 | 397.9 | 291.4 | 291.4 | 3500 | 3500 | 3500 | 115900 | 1040000 | Ivoire clair | Ivoire clair | 1043527 | 934964 | 9 | 291.413 | 3580.92 | 115947 | 103885 | ...de stratigraphies = default; ...de matériaux et couleurs = Ivoire clair; ...de matériaux et couleurs - 1 = Ivoire clair; ...de matériaux et couleurs - 2 = Ivoire clair
Enveloppe 311702 | Rez-de-Jardin | Enveloppe | 311702 | 366 | 9000 | 1552655706 | 1552655706 | 0 | 1 | 0550 | 02 | Rez-de-Jardin | no | rectangle | 201.489 | 291.413 | -1.94511e-11 | 89.9992 | 291.413 | 269.999 | HAUT Rez-de-Jardin (Rez-de-chaussée 1047) | 0.0128504 | <aucun> | Rez-de-Jardin (Rez-de-Jardin 15545) | <aucun> | 201.5 | 201.5 | 291.4 | 291.4 | 1900 | 1900 | 1900 | 58700 | 530000 | 18 Travertin romain | 18 Travertin romain | 528450 | 528450 | 9 | 291.413 | 1813.4 | 58716.6 | 58716.6 | ...de stratigraphies = default; ...de matériaux et couleurs = 18 Travertin romain; ...de matériaux et couleurs - 1 = 18 Travertin romain; ...de matériaux et couleurs - 2 = 18 Travertin romain
Enveloppe 311761 | Rez-de-Jardin | Enveloppe | 311761 | 366 | 9000 | 1552655706 | 1552655706 | 0 | 1 | 0551 | 02 | Rez-de-Jardin | no | rectangle | 181.953 | 291.413 | -1.94511e-11 | 179.897 | 291.413 | 359.897 | HAUT Rez-de-Jardin (Rez-de-chaussée 1047) | 0.0128504 | <aucun> | Rez-de-Jardin (Rez-de-Jardin 15545) | <aucun> | 182 | 182 | 291.4 | 291.4 | 1600 | 1600 | 1600 | 53000 | 480000 | 18 Travertin romain | 18 Travertin romain | 477213 | 477213 | 9 | 291.413 | 1637.58 | 53023.6 | 53023.6 | ...de stratigraphies = default; ...de matériaux et couleurs = 18 Travertin romain; ...de matériaux et couleurs - 1 = 18 Travertin romain; ...de matériaux et couleurs - 2 = 18 Travertin romain
Enveloppe 356643 | Rez-de-Jardin | Enveloppe | 356643 | 366 | 9000 | 1552655706 | 1552655706 | 1 | 1 | 0573 | 02 | Rez-de-Jardin | no | rectangle | 251.077 | 291.413 | -1.94511e-11 | 0.286132 | 291.413 | 180.286 | HAUT Rez-de-Jardin (Rez-de-chaussée 1047) | 0.0128504 | <aucun> | Rez-de-Jardin (Rez-de-Jardin 15545) | <aucun> | 251.1 | 251.1 | 291.4 | 291.4 | 2300 | 2300 | 2300 | 73200 | 660000 | 18 Travertin romain | 18 Travertin romain | 658504 | 658504 | 9 | 291.413 | 2259.69 | 73167.1 | 73167.1 | ...de stratigraphies = default; ...de matériaux et couleurs = 18 Travertin romain; ...de matériaux et couleurs - 1 = 18 Travertin romain; ...de matériaux et couleurs - 2 = 18 Travertin romain
Enveloppe 310460 | Rez-de-Jardin | Enveloppe | 310460 | 366 | 9000 | 1552655706 | 1552655706 | 0 | 1 | 0544 | 02 | Rez-de-Jardin | no | rectangle | 200.401 | 291.413 | -1.94511e-11 | 89.7309 | 291.413 | 269.731 | HAUT Rez-de-Jardin (Rez-de-chaussée 1047) | 0.0128504 | <aucun> | Rez-de-Jardin (Rez-de-Jardin 15545) | <aucun> | 200.4 | 200.4 | 291.4 | 291.4 | 1800 | 1800 | 1800 | 58400 | 530000 | 18 Travertin romain | 18 Travertin romain | 525595 | 525595 | 9 | 291.413 | 1803.61 | 58399.5 | 58399.5 | ...de stratigraphies = default; ...de matériaux et couleurs = 18 Travertin romain; ...de matériaux et couleurs - 1 = 18 Travertin romain; ...de matériaux et couleurs - 2 = 18 Travertin romain
Enveloppe courbe 595254 | Rez-de-Jardin | Enveloppe courbe | 595254 | 367 | 9001 | -746779066 | -746779066 | 0 | 0 | 47 | 02 | Rez-de-Jardin | no | rectangle | 67.5383 | 291.413 | 7.4607e-12 | 25.4132 | 291.413 | 205.413 | HAUT Rez-de-Jardin (Rez-de-chaussée 1047) | 0.0128504 | <aucun> | Rez-de-Jardin (Rez-de-Jardin 15545) | <aucun> | 67.5 | 67.5 | 291.4 | 291.4 | 400 | 600 | 600 | 19700 | 180000 | Blanc | Blanc | 176451 | 176451 | 8.96529 | 291.413 | 605.5 | 19681.6 | 19681.6 | ...de matériaux et couleurs = Blanc; ...de matériaux et couleurs - 1 = Blanc; ...de matériaux et couleurs - 2 = Blanc; ...de stratigraphies = default | IFC_Pset_Géométrie - Rayon: 152.27 cm; Point arc: [829,6; -375,7] cm; Centre: [682,7; -392,5] cm; Angle de la Tangente: 10.13 deg
Enveloppe 378519 | Rez-de-chaussée | Enveloppe | 378519 | 366 | 9000 | 1977773087 | 1977773087 | 1 | 0 | 0664 | 03 | Rez-de-chaussée | no | rectangle | 27.996 | 477.795 | 0.0128504 | 0.180664 | 477.795 | 180.181 | HAUT Rez-de-chaussée (Niveau 1 2343) | 0.0128504 | <aucun> | Rez-de-chaussée (Rez-de-chaussée 1047) | <aucun> | 28 | 28 | 477.8 | 477.8 | 300 | 300 | 300 | 13400 | 120000 | Ivoire clair | Ivoire clair | 120387 | 120387 | 9 | 477.795 | 251.964 | 13376.4 | 13376.4 | ...de stratigraphies = default; ...de matériaux et couleurs = Ivoire clair; ...de matériaux et couleurs - 1 = Ivoire clair; ...de matériaux et couleurs - 2 = Ivoire clair
Enveloppe 378223 | Rez-de-chaussée | Enveloppe | 378223 | 366 | 9000 | 1977773087 | 1977773087 | 1 | 0 | 0662 | 03 | Rez-de-chaussée | no | rectangle | 61.5411 | 477.795 | 0.0128504 | 0.0864368 | 477.795 | 180.086 | HAUT Rez-de-chaussée (Niveau 1 2343) | 0.0128504 | <aucun> | Rez-de-chaussée (Rez-de-chaussée 1047) | <aucun> | 61.5 | 61.5 | 477.8 | 477.8 | 600 | 600 | 600 | 29400 | 260000 | Ivoire clair | Ivoire clair | 264636 | 264636 | 9 | 477.795 | 553.87 | 29404.1 | 29404.1 | ...de stratigraphies = default; ...de matériaux et couleurs = Ivoire clair; ...de matériaux et couleurs - 1 = Ivoire clair; ...de matériaux et couleurs - 2 = Ivoire clair
Enveloppe 376068 | Rez-de-chaussée | Enveloppe | 376068 | 366 | 9000 | 1977773087 | 1977773087 | 0 | 1 | 0655 | 03 | Rez-de-chaussée | no | rectangle | 188.359 | 477.795 | 0.0128504 | 89.3023 | 477.795 | 269.302 | HAUT Rez-de-chaussée (Niveau 1 2343) | 0.0128504 | <aucun> | Rez-de-chaussée (Rez-de-chaussée 1047) | <aucun> | 188.4 | 188.4 | 477.8 | 477.8 | 1700 | 1700 | 1700 | 90000 | 810000 | Ivoire clair | Ivoire clair | 809972 | 637745 | 9 | 477.795 | 1695.23 | 89996.9 | 70860.6 | ...de stratigraphies = default; ...de matériaux et couleurs = Ivoire clair; ...de matériaux et couleurs - 1 = Ivoire clair; ...de matériaux et couleurs - 2 = Ivoire clair
Enveloppe 376135 | Rez-de-chaussée | Enveloppe | 376135 | 366 | 9000 | 1977773087 | 1977773087 | 1 | 1 | 0656 | 03 | Rez-de-chaussée | no | rectangle | 27.4704 | 477.795 | 0.0128504 | 0.321354 | 477.795 | 180.321 | HAUT Rez-de-chaussée (Niveau 1 2343) | 0.0128504 | <aucun> | Rez-de-chaussée (Rez-de-chaussée 1047) | <aucun> | 27.5 | 27.5 | 477.8 | 477.8 | 200 | 200 | 200 | 13100 | 120000 | Ivoire clair | Ivoire clair | 118127 | 118127 | 9 | 477.795 | 247.234 | 13125.2 | 13125.2 | ...de stratigraphies = default; ...de matériaux et couleurs = Ivoire clair; ...de matériaux et couleurs - 1 = Ivoire clair; ...de matériaux et couleurs - 2 = Ivoire clair
Enveloppe 375883 | Rez-de-chaussée | Enveloppe | 375883 | 366 | 9000 | 1977773087 | 1977773087 | 0 | 1 | 0653 | 03 | Rez-de-chaussée | no | rectangle | 191.341 | 477.795 | 0.0128504 | 179.703 | 477.795 | 359.703 | HAUT Rez-de-chaussée (Niveau 1 2343) | 0.0128504 | <aucun> | Rez-de-chaussée (Rez-de-chaussée 1047) | <aucun> | 191.3 | 191.3 | 477.8 | 477.8 | 1700 | 1700 | 1700 | 91400 | 820000 | Ivoire clair | Ivoire clair | 822796 | 822796 | 9 | 477.795 | 1722.07 | 91421.8 | 91421.8 | ...de stratigraphies = default; ...de matériaux et couleurs = Ivoire clair; ...de matériaux et couleurs - 1 = Ivoire clair; ...de matériaux et couleurs - 2 = Ivoire clair
Enveloppe 375942 | Rez-de-chaussée | Enveloppe | 375942 | 366 | 9000 | 1977773087 | 1977773087 | 0 | 1 | 0654 | 03 | Rez-de-chaussée | no | rectangle | 63.7757 | 477.795 | 0.0128504 | 178.605 | 477.795 | 358.605 | HAUT Rez-de-chaussée (Niveau 1 2343) | 0.0128504 | <aucun> | Rez-de-chaussée (Rez-de-chaussée 1047) | <aucun> | 63.8 | 63.8 | 477.8 | 477.8 | 600 | 600 | 600 | 30500 | 270000 | Ivoire clair | Ivoire clair | 274245 | 274245 | 9 | 477.795 | 573.981 | 30471.7 | 30471.7 | ...de stratigraphies = default; ...de matériaux et couleurs = Ivoire clair; ...de matériaux et couleurs - 1 = Ivoire clair; ...de matériaux et couleurs - 2 = Ivoire clair
Enveloppe 369010 | Rez-de-chaussée | Enveloppe | 369010 | 366 | 9000 | 1977773087 | 1977773087 | 1 | 0 | 0603 | 03 | Rez-de-chaussée | no | rectangle | 113.424 | 477.795 | 0.0128504 | 90.174 | 477.795 | 270.174 | HAUT Rez-de-chaussée (Niveau 1 2343) | 0.0128504 | <aucun> | Rez-de-chaussée (Rez-de-chaussée 1047) | <aucun> | 113.4 | 113.4 | 477.8 | 477.8 | 1000 | 1000 | 1000 | 54200 | 490000 | Ivoire clair | Ivoire clair | 487739 | 487739 | 9 | 477.795 | 1020.81 | 54193.3 | 54193.3 | ...de stratigraphies = default; ...de matériaux et couleurs = Ivoire clair; ...de matériaux et couleurs - 1 = Ivoire clair; ...de matériaux et couleurs - 2 = Ivoire clair
Enveloppe 369829 | Rez-de-chaussée | Enveloppe | 369829 | 366 | 9000 | 1977773087 | 1977773087 | 1 | 1 | 0609 | 03 | Rez-de-chaussée | no | rectangle | 230.87 | 477.795 | 0.0128504 | 179.806 | 477.795 | 359.806 | HAUT Rez-de-chaussée (Niveau 1 2343) | 0.0128504 | <aucun> | Rez-de-chaussée (Rez-de-chaussée 1047) | <aucun> | 230.9 | 230.9 | 477.8 | 477.8 | 2100 | 2100 | 2100 | 110300 | 990000 | Ivoire clair | Ivoire clair | 992775 | 992775 | 9 | 477.795 | 2077.83 | 110308 | 110308 | ...de stratigraphies = default; ...de matériaux et couleurs = Ivoire clair; ...de matériaux et couleurs - 1 = Ivoire clair; ...de matériaux et couleurs - 2 = Ivoire clair
Enveloppe 369832 | Rez-de-chaussée | Enveloppe | 369832 | 366 | 9000 | 1977773087 | 1977773087 | 0 | 1 | 0610 | 03 | Rez-de-chaussée | no | rectangle | 102.064 | 477.795 | 0.0128504 | 90.4214 | 477.795 | 270.421 | HAUT Rez-de-chaussée (Niveau 1 2343) | 0.0128504 | <aucun> | Rez-de-chaussée (Rez-de-chaussée 1047) | <aucun> | 102.1 | 102.1 | 477.8 | 477.8 | 900 | 900 | 900 | 48800 | 440000 | Ivoire clair | Ivoire clair | 438891 | 438891 | 9 | 477.795 | 918.576 | 48765.7 | 48765.7 | ...de stratigraphies = default; ...de matériaux et couleurs = Ivoire clair; ...de matériaux et couleurs - 1 = Ivoire clair; ...de matériaux et couleurs - 2 = Ivoire clair
Enveloppe 369825 | Rez-de-chaussée | Enveloppe | 369825 | 366 | 9000 | 1977773087 | 1977773087 | 1 | 1 | 0608 | 03 | Rez-de-chaussée | no | rectangle | 233.042 | 477.795 | 0.0128504 | 179.806 | 477.795 | 359.806 | HAUT Rez-de-chaussée (Niveau 1 2343) | 0.0128504 | <aucun> | Rez-de-chaussée (Rez-de-chaussée 1047) | <aucun> | 233 | 233 | 477.8 | 477.8 | 2100 | 2100 | 2100 | 111300 | 1000000 | Ivoire clair | Ivoire clair | 1002119 | 1002119 | 9 | 477.795 | 2097.38 | 111347 | 111347 | ...de stratigraphies = default; ...de matériaux et couleurs = Ivoire clair; ...de matériaux et couleurs - 1 = Ivoire clair; ...de matériaux et couleurs - 2 = Ivoire clair
Enveloppe 367727 | Rez-de-chaussée | Enveloppe | 367727 | 366 | 9000 | 1977773087 | 1977773087 | 0 | 1 | 0595 | 03 | Rez-de-chaussée | no | rectangle | 213.416 | 477.795 | 0.0128504 | 179.915 | 477.795 | 359.915 | HAUT Rez-de-chaussée (Niveau 1 2343) | 0.0128504 | <aucun> | Rez-de-chaussée (Rez-de-chaussée 1047) | <aucun> | 213.4 | 213.4 | 477.8 | 477.8 | 1900 | 1900 | 1900 | 102000 | 920000 | Ivoire clair | Ivoire clair | 917724 | 917724 | 9 | 477.795 | 1920.75 | 101969 | 101969 | ...de stratigraphies = default; ...de matériaux et couleurs = Ivoire clair; ...de matériaux et couleurs - 1 = Ivoire clair; ...de matériaux et couleurs - 2 = Ivoire clair
Enveloppe 367625 | Rez-de-chaussée | Enveloppe | 367625 | 366 | 9000 | 1977773087 | 1977773087 | 1 | 1 | 0593 | 03 | Rez-de-chaussée | no | rectangle | 26.3197 | 477.795 | 0.0128504 | 88.9864 | 477.795 | 268.986 | HAUT Rez-de-chaussée (Niveau 1 2343) | 0.0128504 | <aucun> | Rez-de-chaussée (Rez-de-chaussée 1047) | <aucun> | 26.3 | 26.3 | 477.8 | 477.8 | 200 | 200 | 200 | 12600 | 110000 | Ivoire clair | Ivoire clair | 113179 | 113179 | 9 | 477.795 | 236.877 | 12575.4 | 12575.4 | ...de stratigraphies = default; ...de matériaux et couleurs = Ivoire clair; ...de matériaux et couleurs - 1 = Ivoire clair; ...de matériaux et couleurs - 2 = Ivoire clair
Enveloppe 367684 | Rez-de-chaussée | Enveloppe | 367684 | 366 | 9000 | 1977773087 | 1977773087 | 1 | 1 | 0594 | 03 | Rez-de-chaussée | no | rectangle | 28.3504 | 477.795 | 0.0128504 | 88.4737 | 477.795 | 268.474 | HAUT Rez-de-chaussée (Niveau 1 2343) | 0.0128504 | <aucun> | Rez-de-chaussée (Rez-de-chaussée 1047) | <aucun> | 28.4 | 28.4 | 477.8 | 477.8 | 300 | 300 | 300 | 13600 | 120000 | Ivoire clair | Ivoire clair | 121911 | 121911 | 9 | 477.795 | 255.153 | 13545.7 | 13545.7 | ...de stratigraphies = default; ...de matériaux et couleurs = Ivoire clair; ...de matériaux et couleurs - 1 = Ivoire clair; ...de matériaux et couleurs - 2 = Ivoire clair
Enveloppe 368501 | Rez-de-chaussée | Enveloppe | 368501 | 366 | 9000 | 1977773087 | 1977773087 | 1 | 1 | 0600 | 03 | Rez-de-chaussée | no | rectangle | 95.3795 | 477.795 | 0.0128504 | 90.336 | 477.795 | 270.336 | HAUT Rez-de-chaussée (Niveau 1 2343) | 0.0128504 | <aucun> | Rez-de-chaussée (Rez-de-chaussée 1047) | <aucun> | 95.4 | 95.4 | 477.8 | 477.8 | 900 | 900 | 900 | 45600 | 410000 | Ivoire clair | Ivoire clair | 410147 | 410147 | 9 | 477.795 | 858.416 | 45571.9 | 45571.9 | ...de stratigraphies = default; ...de matériaux et couleurs = Ivoire clair; ...de matériaux et couleurs - 1 = Ivoire clair; ...de matériaux et couleurs - 2 = Ivoire clair
Enveloppe 368626 | Rez-de-chaussée | Enveloppe | 368626 | 366 | 9000 | 1977773087 | 1977773087 | 1 | 1 | 0601 | 03 | Rez-de-chaussée | no | rectangle | 71.0269 | 477.795 | 0.0128504 | 89.4489 | 477.795 | 269.449 | HAUT Rez-de-chaussée (Niveau 1 2343) | 0.0128504 | <aucun> | Rez-de-chaussée (Rez-de-chaussée 1047) | <aucun> | 71 | 71 | 477.8 | 477.8 | 600 | 600 | 600 | 33900 | 310000 | Ivoire clair | Ivoire clair | 305427 | 305427 | 9 | 477.795 | 639.242 | 33936.3 | 33936.3 | ...de stratigraphies = default; ...de matériaux et couleurs = Ivoire clair; ...de matériaux et couleurs - 1 = Ivoire clair; ...de matériaux et couleurs - 2 = Ivoire clair
Enveloppe 368208 | Rez-de-chaussée | Enveloppe | 368208 | 366 | 9000 | 1977773087 | 1977773087 | 1 | 1 | 0598 | 03 | Rez-de-chaussée | no | rectangle | 166.726 | 477.795 | 0.0128504 | 89.71 | 477.795 | 269.71 | HAUT Rez-de-chaussée (Niveau 1 2343) | 0.0128504 | <aucun> | Rez-de-chaussée (Rez-de-chaussée 1047) | <aucun> | 166.7 | 166.7 | 477.8 | 477.8 | 1500 | 1500 | 1500 | 79600 | 720000 | Ivoire clair | Ivoire clair | 716946 | 716946 | 9 | 477.795 | 1500.53 | 79660.7 | 79660.7 | ...de stratigraphies = default; ...de matériaux et couleurs = Ivoire clair; ...de matériaux et couleurs - 1 = Ivoire clair; ...de matériaux et couleurs - 2 = Ivoire clair
Enveloppe 372191 | Rez-de-chaussée | Enveloppe | 372191 | 366 | 9000 | 1422992700 | 1977773087 | 0 | 1 | 0622 | 03 | Rez-de-chaussée | no | rectangle | 131.363 | 182.783 | 0.0128504 | 89.7309 | 182.783 | 269.731 | HAUT Rez-de-chaussée (Niveau 1 2343) | -295 | <aucun> | Rez-de-chaussée (Rez-de-chaussée 1047) | <aucun> | 131.4 | 131.4 | 182.8 | 182.8 | 1200 | 1200 | 1200 | 24000 | 220000 | Blanc gris | Ivoire clair | 216097 | 216097 | 9 | 182.783 | 1182.26 | 24010.8 | 24010.8 | ...de stratigraphies = default; ...de matériaux et couleurs - 1 = Ivoire clair; ...de matériaux et couleurs - 2 = Ivoire clair; ...de matériaux et couleurs = Blanc gris
Enveloppe 372315 | Rez-de-chaussée | Enveloppe | 372315 | 366 | 9000 | 1422992700 | 1977773087 | 0 | 1 | 0623 | 03 | Rez-de-chaussée | no | rectangle | 131.602 | 182.783 | 0.0128504 | 89.9992 | 182.783 | 269.999 | HAUT Rez-de-chaussée (Niveau 1 2343) | -295 | <aucun> | Rez-de-chaussée (Rez-de-chaussée 1047) | <aucun> | 131.6 | 131.6 | 182.8 | 182.8 | 1200 | 1200 | 1200 | 24100 | 220000 | Blanc gris | Ivoire clair | 216490 | 216490 | 9 | 182.783 | 1184.41 | 24054.5 | 24054.5 | ...de stratigraphies = default; ...de matériaux et couleurs - 1 = Ivoire clair; ...de matériaux et couleurs - 2 = Ivoire clair; ...de matériaux et couleurs = Blanc gris
Enveloppe 371899 | Rez-de-chaussée | Enveloppe | 371899 | 366 | 9000 | 1977773087 | 1977773087 | 0 | 1 | 0620 | 03 | Rez-de-chaussée | no | rectangle | 161.766 | 477.795 | 0.0128504 | 89.7205 | 477.795 | 269.72 | HAUT Rez-de-chaussée (Niveau 1 2343) | 0.0128504 | <aucun> | Rez-de-chaussée (Rez-de-chaussée 1047) | <aucun> | 161.8 | 161.8 | 477.8 | 477.8 | 1500 | 1500 | 1500 | 77300 | 700000 | Ivoire clair | Ivoire clair | 695618 | 695618 | 9 | 477.795 | 1455.89 | 77290.9 | 77290.9 | ...de stratigraphies = default; ...de matériaux et couleurs = Ivoire clair; ...de matériaux et couleurs - 1 = Ivoire clair; ...de matériaux et couleurs - 2 = Ivoire clair
Enveloppe 372021 | Rez-de-chaussée | Enveloppe | 372021 | 366 | 9000 | 1977773087 | 1977773087 | 1 | 1 | 0621 | 03 | Rez-de-chaussée | no | rectangle | 50.3513 | 477.795 | 0.0128504 | 179.458 | 477.795 | 359.458 | HAUT Rez-de-chaussée (Niveau 1 2343) | 0.0128504 | <aucun> | Rez-de-chaussée (Rez-de-chaussée 1047) | <aucun> | 50.4 | 50.4 | 477.8 | 477.8 | 500 | 500 | 500 | 24100 | 220000 | Ivoire clair | Ivoire clair | 216518 | 216518 | 9 | 477.795 | 453.161 | 24057.6 | 24057.6 | ...de stratigraphies = default; ...de matériaux et couleurs = Ivoire clair; ...de matériaux et couleurs - 1 = Ivoire clair; ...de matériaux et couleurs - 2 = Ivoire clair
Enveloppe 372645 | Rez-de-chaussée | Enveloppe | 372645 | 366 | 9000 | 1977773087 | 1977773087 | 0 | 1 | 0624 | 03 | Rez-de-chaussée | no | rectangle | 131.81 | 477.795 | 0.0128504 | 179.897 | 477.795 | 359.897 | HAUT Rez-de-chaussée (Niveau 1 2343) | 0.0128504 | <aucun> | Rez-de-chaussée (Rez-de-chaussée 1047) | <aucun> | 131.8 | 131.8 | 477.8 | 477.8 | 1200 | 1200 | 1200 | 63000 | 570000 | Ivoire clair | Ivoire clair | 566804 | 566804 | 9 | 477.795 | 1186.29 | 62978.2 | 62978.2 | ...de stratigraphies = default; ...de matériaux et couleurs = Ivoire clair; ...de matériaux et couleurs - 1 = Ivoire clair; ...de matériaux et couleurs - 2 = Ivoire clair
Enveloppe 372935 | Rez-de-chaussée | Enveloppe | 372935 | 366 | 9000 | 1977773087 | 1977773087 | 0 | 1 | 0627 | 03 | Rez-de-chaussée | no | rectangle | 84.5395 | 477.795 | 0.0128504 | 45.0217 | 477.795 | 225.022 | HAUT Rez-de-chaussée (Niveau 1 2343) | 0.0128504 | <aucun> | Rez-de-chaussée (Rez-de-chaussée 1047) | <aucun> | 84.5 | 84.5 | 477.8 | 477.8 | 800 | 800 | 800 | 40400 | 360000 | Ivoire clair | Ivoire clair | 363533 | 363533 | 9 | 477.795 | 760.855 | 40392.6 | 40392.6 | ...de stratigraphies = default; ...de matériaux et couleurs = Ivoire clair; ...de matériaux et couleurs - 1 = Ivoire clair; ...de matériaux et couleurs - 2 = Ivoire clair
Enveloppe 373104 | Rez-de-chaussée | Enveloppe | 373104 | 366 | 9000 | 1977773087 | 1977773087 | 0 | 1 | 0628 | 03 | Rez-de-chaussée | no | rectangle | 191.76 | 477.795 | 0.0128504 | 89.8114 | 477.795 | 269.811 | HAUT Rez-de-chaussée (Niveau 1 2343) | 0.0128504 | <aucun> | Rez-de-chaussée (Rez-de-chaussée 1047) | <aucun> | 191.8 | 191.8 | 477.8 | 477.8 | 1700 | 1700 | 1700 | 91600 | 820000 | Ivoire clair | Ivoire clair | 824599 | 824599 | 9 | 477.795 | 1725.84 | 91622.1 | 91622.1 | ...de stratigraphies = default; ...de matériaux et couleurs = Ivoire clair; ...de matériaux et couleurs - 1 = Ivoire clair; ...de matériaux et couleurs - 2 = Ivoire clair
Enveloppe 372767 | Rez-de-chaussée | Enveloppe | 372767 | 366 | 9000 | 1977773087 | 1977773087 | 0 | 1 | 0625 | 03 | Rez-de-chaussée | no | rectangle | 32.4671 | 477.795 | 0.0128504 | 89.062 | 477.795 | 269.062 | HAUT Rez-de-chaussée (Niveau 1 2343) | 0.0128504 | <aucun> | Rez-de-chaussée (Rez-de-chaussée 1047) | <aucun> | 32.5 | 32.5 | 477.8 | 477.8 | 300 | 300 | 300 | 15500 | 140000 | Ivoire clair | Ivoire clair | 139614 | 139614 | 9 | 477.795 | 292.204 | 15512.6 | 15512.6 | ...de stratigraphies = default; ...de matériaux et couleurs = Ivoire clair; ...de matériaux et couleurs - 1 = Ivoire clair; ...de matériaux et couleurs - 2 = Ivoire clair
Enveloppe 372811 | Rez-de-chaussée | Enveloppe | 372811 | 366 | 9000 | 1977773087 | 1977773087 | 0 | 1 | 0626 | 03 | Rez-de-chaussée | no | rectangle | 127.869 | 477.795 | 0.0128504 | 89.8788 | 477.795 | 269.879 | HAUT Rez-de-chaussée (Niveau 1 2343) | 0.0128504 | <aucun> | Rez-de-chaussée (Rez-de-chaussée 1047) | <aucun> | 127.9 | 127.9 | 477.8 | 477.8 | 1200 | 1200 | 1200 | 61100 | 550000 | Ivoire clair | Ivoire clair | 549858 | 549858 | 9 | 477.795 | 1150.82 | 61095.4 | 61095.4 | ...de stratigraphies = default; ...de matériaux et couleurs = Ivoire clair; ...de matériaux et couleurs - 1 = Ivoire clair; ...de matériaux et couleurs - 2 = Ivoire clair
Enveloppe 370044 | Rez-de-chaussée | Enveloppe | 370044 | 366 | 9000 | 1977773087 | 1977773087 | 1 | 1 | 0613 | 03 | Rez-de-chaussée | no | rectangle | 90.8935 | 477.795 | 0.0128504 | 179.931 | 477.795 | 359.931 | HAUT Rez-de-chaussée (Niveau 1 2343) | 0.0128504 | <aucun> | Rez-de-chaussée (Rez-de-chaussée 1047) | <aucun> | 90.9 | 90.9 | 477.8 | 477.8 | 800 | 800 | 800 | 43400 | 390000 | Ivoire clair | Ivoire clair | 390857 | 390857 | 9 | 477.795 | 818.042 | 43428.5 | 43428.5 | ...de stratigraphies = default; ...de matériaux et couleurs = Ivoire clair; ...de matériaux et couleurs - 1 = Ivoire clair; ...de matériaux et couleurs - 2 = Ivoire clair
Enveloppe 370249 | Rez-de-chaussée | Enveloppe | 370249 | 366 | 9000 | 1977773087 | 1977773087 | 1 | 1 | 0614 | 03 | Rez-de-chaussée | no | rectangle | 62.8416 | 477.795 | 0.0128504 | 179.931 | 477.795 | 359.931 | HAUT Rez-de-chaussée (Niveau 1 2343) | 0.0128504 | <aucun> | Rez-de-chaussée (Rez-de-chaussée 1047) | <aucun> | 62.8 | 62.8 | 477.8 | 477.8 | 600 | 600 | 600 | 30000 | 270000 | Ivoire clair | Ivoire clair | 270229 | 270229 | 9 | 477.795 | 565.575 | 30025.4 | 30025.4 | ...de stratigraphies = default; ...de matériaux et couleurs = Ivoire clair; ...de matériaux et couleurs - 1 = Ivoire clair; ...de matériaux et couleurs - 2 = Ivoire clair
Enveloppe 369875 | Rez-de-chaussée | Enveloppe | 369875 | 366 | 9000 | 1977773087 | 1977773087 | 1 | 1 | 0611 | 03 | Rez-de-chaussée | no | rectangle | 64.2881 | 477.795 | 0.0128504 | 179.86 | 477.795 | 359.86 | HAUT Rez-de-chaussée (Niveau 1 2343) | 0.0128504 | <aucun> | Rez-de-chaussée (Rez-de-chaussée 1047) | <aucun> | 64.3 | 64.3 | 477.8 | 477.8 | 600 | 600 | 600 | 30700 | 280000 | Ivoire clair | Ivoire clair | 276449 | 276449 | 9 | 477.795 | 578.593 | 30716.6 | 30716.6 | ...de stratigraphies = default; ...de matériaux et couleurs = Ivoire clair; ...de matériaux et couleurs - 1 = Ivoire clair; ...de matériaux et couleurs - 2 = Ivoire clair
Enveloppe 369919 | Rez-de-chaussée | Enveloppe | 369919 | 366 | 9000 | 1977773087 | 1977773087 | 1 | 1 | 0612 | 03 | Rez-de-chaussée | no | rectangle | 91.0496 | 477.795 | 0.0128504 | 179.86 | 477.795 | 359.86 | HAUT Rez-de-chaussée (Niveau 1 2343) | 0.0128504 | <aucun> | Rez-de-chaussée (Rez-de-chaussée 1047) | <aucun> | 91 | 91 | 477.8 | 477.8 | 800 | 800 | 800 | 43500 | 390000 | Ivoire clair | Ivoire clair | 391528 | 391528 | 9 | 477.795 | 819.447 | 43503.1 | 43503.1 | ...de stratigraphies = default; ...de matériaux et couleurs = Ivoire clair; ...de matériaux et couleurs - 1 = Ivoire clair; ...de matériaux et couleurs - 2 = Ivoire clair
Enveloppe 370373 | Rez-de-chaussée | Enveloppe | 370373 | 366 | 9000 | 1977773087 | 1977773087 | 1 | 1 | 0615 | 03 | Rez-de-chaussée | no | rectangle | 99.3109 | 477.795 | 0.0128504 | 89.8565 | 477.795 | 269.856 | HAUT Rez-de-chaussée (Niveau 1 2343) | 0.0128504 | <aucun> | Rez-de-chaussée (Rez-de-chaussée 1047) | <aucun> | 99.3 | 99.3 | 477.8 | 477.8 | 900 | 900 | 900 | 47400 | 430000 | Ivoire clair | Ivoire clair | 427052 | 427052 | 9 | 477.795 | 893.798 | 47450.3 | 47450.3 | ...de stratigraphies = default; ...de matériaux et couleurs = Ivoire clair; ...de matériaux et couleurs - 1 = Ivoire clair; ...de matériaux et couleurs - 2 = Ivoire clair
Enveloppe 371685 | Rez-de-chaussée | Enveloppe | 371685 | 366 | 9000 | 1977773087 | 1977773087 | 0 | 1 | 0619 | 03 | Rez-de-chaussée | no | rectangle | 165.289 | 477.795 | 0.0128504 | 89.8195 | 477.795 | 269.819 | HAUT Rez-de-chaussée (Niveau 1 2343) | 0.0128504 | <aucun> | Rez-de-chaussée (Rez-de-chaussée 1047) | <aucun> | 165.3 | 165.3 | 477.8 | 477.8 | 1500 | 1500 | 1500 | 79000 | 710000 | Ivoire clair | Ivoire clair | 710768 | 710768 | 9 | 477.795 | 1487.6 | 78974.2 | 78974.2 | ...de stratigraphies = default; ...de matériaux et couleurs = Ivoire clair; ...de matériaux et couleurs - 1 = Ivoire clair; ...de matériaux et couleurs - 2 = Ivoire clair
Enveloppe 370416 | Rez-de-chaussée | Enveloppe | 370416 | 366 | 9000 | 1977773087 | 1977773087 | 1 | 1 | 0616 | 03 | Rez-de-chaussée | no | rectangle | 166.054 | 477.795 | 0.0128504 | 179.862 | 477.795 | 359.862 | HAUT Rez-de-chaussée (Niveau 1 2343) | 0.0128504 | <aucun> | Rez-de-chaussée (Rez-de-chaussée 1047) | <aucun> | 166.1 | 166.1 | 477.8 | 477.8 | 1500 | 1500 | 1500 | 79400 | 710000 | Ivoire clair | Ivoire clair | 714059 | 714059 | 9 | 477.795 | 1494.49 | 79339.9 | 79339.9 | ...de stratigraphies = default; ...de matériaux et couleurs = Ivoire clair; ...de matériaux et couleurs - 1 = Ivoire clair; ...de matériaux et couleurs - 2 = Ivoire clair
Enveloppe 370541 | Rez-de-chaussée | Enveloppe | 370541 | 366 | 9000 | 1977773087 | 1977773087 | 1 | 1 | 0617 | 03 | Rez-de-chaussée | no | rectangle | 166.157 | 477.795 | 0.0128504 | 179.862 | 477.795 | 359.862 | HAUT Rez-de-chaussée (Niveau 1 2343) | 0.0128504 | <aucun> | Rez-de-chaussée (Rez-de-chaussée 1047) | <aucun> | 166.2 | 166.2 | 477.8 | 477.8 | 1500 | 1500 | 1500 | 79400 | 710000 | Ivoire clair | Ivoire clair | 714502 | 714502 | 9 | 477.795 | 1495.42 | 79389.2 | 79389.2 | ...de stratigraphies = default; ...de matériaux et couleurs = Ivoire clair; ...de matériaux et couleurs - 1 = Ivoire clair; ...de matériaux et couleurs - 2 = Ivoire clair
Enveloppe 768435 | Rez-de-chaussée | Enveloppe | 768435 | 366 | 9000 | 1977773087 | 1977773087 | 1 | 0 | 1103 | 03 | Rez-de-chaussée | no | rectangle | 139.355 | 477.795 | 0.0128504 | 0.0151137 | 477.795 | 180.015 | HAUT Rez-de-chaussée (Niveau 1 2343) | 0.0128504 | <aucun> | Rez-de-chaussée (Rez-de-chaussée 1047) | <aucun> | 139.4 | 139.4 | 477.8 | 477.8 | 1300 | 1300 | 1300 | 66600 | 600000 | Ivoire clair | Ivoire clair | 599248 | 244483 | 9 | 477.795 | 1254.19 | 66583.1 | 27164.8 | ...de stratigraphies = default; ...de matériaux et couleurs = Ivoire clair; ...de matériaux et couleurs - 1 = Ivoire clair; ...de matériaux et couleurs - 2 = Ivoire clair
Enveloppe 768826 | Rez-de-chaussée | Enveloppe | 768826 | 366 | 9000 | 1977773087 | 1977773087 | 1 | 0 | 1104 | 03 | Rez-de-chaussée | no | rectangle | 59.2646 | 477.795 | 0.0128504 | 89.6756 | 477.795 | 269.676 | HAUT Rez-de-chaussée (Niveau 1 2343) | 0.0128504 | <aucun> | Rez-de-chaussée (Rez-de-chaussée 1047) | <aucun> | 59.3 | 59.3 | 477.8 | 477.8 | 500 | 500 | 500 | 28300 | 250000 | Ivoire clair | Ivoire clair | 254847 | 254847 | 9 | 477.795 | 533.382 | 28316.4 | 28316.4 | ...de stratigraphies = default; ...de matériaux et couleurs = Ivoire clair; ...de matériaux et couleurs - 1 = Ivoire clair; ...de matériaux et couleurs - 2 = Ivoire clair
Enveloppe 768249 | Rez-de-chaussée | Enveloppe | 768249 | 366 | 9000 | 1977773087 | 1977773087 | 1 | 0 | 1101 | 03 | Rez-de-chaussée | no | rectangle | 35.1703 | 477.795 | 0.0128504 | 95.7479 | 477.795 | 275.748 | HAUT Rez-de-chaussée (Niveau 1 2343) | 0.0128504 | <aucun> | Rez-de-chaussée (Rez-de-chaussée 1047) | <aucun> | 35.2 | 35.2 | 477.8 | 477.8 | 300 | 300 | 300 | 16800 | 150000 | Ivoire clair | Ivoire clair | 151238 | 151238 | 9 | 477.795 | 316.533 | 16804.2 | 16804.2 | ...de stratigraphies = default; ...de matériaux et couleurs = Ivoire clair; ...de matériaux et couleurs - 1 = Ivoire clair; ...de matériaux et couleurs - 2 = Ivoire clair
Enveloppe 768434 | Rez-de-chaussée | Enveloppe | 768434 | 366 | 9000 | 1977773087 | 1977773087 | 0 | 0 | 1102 | 03 | Rez-de-chaussée | no | rectangle | 36.0631 | 477.795 | 0.0128504 | 85.797 | 477.795 | 265.797 | HAUT Rez-de-chaussée (Niveau 1 2343) | 0.0128504 | <aucun> | Rez-de-chaussée (Rez-de-chaussée 1047) | <aucun> | 36.1 | 36.1 | 477.8 | 477.8 | 300 | 300 | 300 | 17200 | 150000 | Ivoire clair | Ivoire clair | 155077 | 155077 | 9 | 477.795 | 324.568 | 17230.8 | 17230.8 | ...de stratigraphies = default; ...de matériaux et couleurs = Ivoire clair; ...de matériaux et couleurs - 1 = Ivoire clair; ...de matériaux et couleurs - 2 = Ivoire clair
Enveloppe 769168 | Rez-de-chaussée | Enveloppe | 769168 | 366 | 9000 | 1977773087 | 1977773087 | 1 | 0 | 1105 | 03 | Rez-de-chaussée | no | rectangle | 24.6244 | 477.795 | 0.0128504 | 173.332 | 477.795 | 353.332 | HAUT Rez-de-chaussée (Niveau 1 2343) | 0.0128504 | <aucun> | Rez-de-chaussée (Rez-de-chaussée 1047) | <aucun> | 24.6 | 24.6 | 477.8 | 477.8 | 200 | 200 | 200 | 11800 | 110000 | Ivoire clair | Ivoire clair | 105889 | 105889 | 9 | 477.795 | 221.619 | 11765.4 | 11765.4 | ...de stratigraphies = default; ...de matériaux et couleurs = Ivoire clair; ...de matériaux et couleurs - 1 = Ivoire clair; ...de matériaux et couleurs - 2 = Ivoire clair
Enveloppe 770679 | Rez-de-chaussée | Enveloppe | 770679 | 366 | 9000 | 1977773087 | 1977773087 | 1 | 0 | 1108 | 03 | Rez-de-chaussée | no | rectangle | 39.1674 | 477.795 | 0.0128504 | 176.134 | 477.795 | 356.134 | HAUT Rez-de-chaussée (Niveau 1 2343) | 0.0128504 | <aucun> | Rez-de-chaussée (Rez-de-chaussée 1047) | <aucun> | 39.2 | 39.2 | 477.8 | 477.8 | 400 | 400 | 400 | 18700 | 170000 | Ivoire clair | Ivoire clair | 168426 | 168426 | 9 | 477.795 | 352.506 | 18714 | 18714 | ...de stratigraphies = default; ...de matériaux et couleurs = Ivoire clair; ...de matériaux et couleurs - 1 = Ivoire clair; ...de matériaux et couleurs - 2 = Ivoire clair
Enveloppe 770892 | Rez-de-chaussée | Enveloppe | 770892 | 366 | 9000 | 1977773087 | 1977773087 | 1 | 0 | 1109 | 03 | Rez-de-chaussée | no | rectangle | 89.2977 | 477.795 | 0.0128504 | 89.9047 | 477.795 | 269.905 | HAUT Rez-de-chaussée (Niveau 1 2343) | 0.0128504 | <aucun> | Rez-de-chaussée (Rez-de-chaussée 1047) | <aucun> | 89.3 | 89.3 | 477.8 | 477.8 | 800 | 800 | 800 | 42700 | 380000 | Ivoire clair | Ivoire clair | 383994 | 383994 | 9 | 477.795 | 803.679 | 42666 | 42666 | ...de stratigraphies = default; ...de matériaux et couleurs = Ivoire clair; ...de matériaux et couleurs - 1 = Ivoire clair; ...de matériaux et couleurs - 2 = Ivoire clair
Enveloppe 769384 | Rez-de-chaussée | Enveloppe | 769384 | 366 | 9000 | 1977773087 | 1977773087 | 1 | 0 | 1106 | 03 | Rez-de-chaussée | no | rectangle | 131.776 | 477.795 | 0.0128504 | 89.8351 | 477.795 | 269.835 | HAUT Rez-de-chaussée (Niveau 1 2343) | 0.0128504 | <aucun> | Rez-de-chaussée (Rez-de-chaussée 1047) | <aucun> | 131.8 | 131.8 | 477.8 | 477.8 | 1200 | 1200 | 1200 | 63000 | 570000 | Ivoire clair | Ivoire clair | 566660 | 566660 | 9 | 477.795 | 1185.99 | 62962.2 | 62962.2 | ...de stratigraphies = default; ...de matériaux et couleurs = Ivoire clair; ...de matériaux et couleurs - 1 = Ivoire clair; ...de matériaux et couleurs - 2 = Ivoire clair
Enveloppe 770643 | Rez-de-chaussée | Enveloppe | 770643 | 366 | 9000 | 1977773087 | 1977773087 | 1 | 0 | 1107 | 03 | Rez-de-chaussée | no | rectangle | 24.8967 | 477.795 | 0.0128504 | 3.52739 | 477.795 | 183.527 | HAUT Rez-de-chaussée (Niveau 1 2343) | 0.0128504 | <aucun> | Rez-de-chaussée (Rez-de-chaussée 1047) | <aucun> | 24.9 | 24.9 | 477.8 | 477.8 | 200 | 200 | 200 | 11900 | 110000 | Ivoire clair | Ivoire clair | 107060 | 107060 | 9 | 477.795 | 224.07 | 11895.5 | 11895.5 | ...de stratigraphies = default; ...de matériaux et couleurs = Ivoire clair; ...de matériaux et couleurs - 1 = Ivoire clair; ...de matériaux et couleurs - 2 = Ivoire clair
Enveloppe 752182 | Rez-de-chaussée | Enveloppe | 752182 | 366 | 9000 | 1977773087 | 1977773087 | 1 | 0 | 1094 | 03 | Rez-de-chaussée | no | rectangle | 273.515 | 329.987 | 0.0128504 | 90.3156 | 329.987 | 270.316 | HAUT Rez-de-chaussée (Niveau 1 2343) | -147.795 | <aucun> | Rez-de-chaussée (Rez-de-chaussée 1047) | <aucun> | 273.5 | 273.5 | 330 | 330 | 2500 | 2500 | 2500 | 90300 | 810000 | Ivoire clair | Ivoire clair | 812308 | 335886 | 9 | 329.987 | 2461.64 | 90256.5 | 37320.7 | ...de stratigraphies = default; ...de matériaux et couleurs = Ivoire clair; ...de matériaux et couleurs - 1 = Ivoire clair; ...de matériaux et couleurs - 2 = Ivoire clair
Enveloppe 767057 | Rez-de-chaussée | Enveloppe | 767057 | 366 | 9000 | 1977773087 | 1977773087 | 1 | 0 | 1095 | 03 | Rez-de-chaussée | no | rectangle | 113.383 | 477.795 | 0.0128504 | 179.927 | 477.795 | 359.927 | HAUT Rez-de-chaussée (Niveau 1 2343) | 0.0128504 | <aucun> | Rez-de-chaussée (Rez-de-chaussée 1047) | <aucun> | 113.4 | 113.4 | 477.8 | 477.8 | 1000 | 1000 | 1000 | 54200 | 490000 | Ivoire clair | Ivoire clair | 487563 | 487563 | 9 | 477.795 | 1020.44 | 54173.7 | 54173.7 | ...de stratigraphies = default; ...de matériaux et couleurs = Ivoire clair; ...de matériaux et couleurs - 1 = Ivoire clair; ...de matériaux et couleurs - 2 = Ivoire clair
Enveloppe 767131 | Rez-de-chaussée | Enveloppe | 767131 | 366 | 9000 | 1977773087 | 1977773087 | 0 | 0 | 1096 | 03 | Rez-de-chaussée | no | rectangle | 36.7495 | 477.795 | 0.0128504 | 87.0588 | 477.795 | 267.059 | HAUT Rez-de-chaussée (Niveau 1 2343) | 0.0128504 | <aucun> | Rez-de-chaussée (Rez-de-chaussée 1047) | <aucun> | 36.7 | 36.7 | 477.8 | 477.8 | 300 | 300 | 300 | 17500 | 160000 | Ivoire clair | Ivoire clair | 158029 | 158029 | 9 | 477.795 | 330.745 | 17558.7 | 17558.7 | ...de stratigraphies = default; ...de matériaux et couleurs = Ivoire clair; ...de matériaux et couleurs - 1 = Ivoire clair; ...de matériaux et couleurs - 2 = Ivoire clair
Enveloppe 767814 | Rez-de-chaussée | Enveloppe | 767814 | 366 | 9000 | 1977773087 | 1977773087 | 1 | 0 | 1099 | 03 | Rez-de-chaussée | no | rectangle | 36.1991 | 477.795 | 0.0128504 | 95.3522 | 477.795 | 275.352 | HAUT Rez-de-chaussée (Niveau 1 2343) | 0.0128504 | <aucun> | Rez-de-chaussée (Rez-de-chaussée 1047) | <aucun> | 36.2 | 36.2 | 477.8 | 477.8 | 300 | 300 | 300 | 17300 | 160000 | Ivoire clair | Ivoire clair | 155662 | 155662 | 9 | 477.795 | 325.792 | 17295.8 | 17295.8 | ...de stratigraphies = default; ...de matériaux et couleurs = Ivoire clair; ...de matériaux et couleurs - 1 = Ivoire clair; ...de matériaux et couleurs - 2 = Ivoire clair
Enveloppe 768034 | Rez-de-chaussée | Enveloppe | 768034 | 366 | 9000 | 1977773087 | 1977773087 | 1 | 0 | 1100 | 03 | Rez-de-chaussée | no | rectangle | 20.4708 | 477.795 | 0.0128504 | 179.927 | 477.795 | 359.927 | HAUT Rez-de-chaussée (Niveau 1 2343) | 0.0128504 | <aucun> | Rez-de-chaussée (Rez-de-chaussée 1047) | <aucun> | 20.5 | 20.5 | 477.8 | 477.8 | 200 | 200 | 200 | 9800 | 90000 | Ivoire clair | Ivoire clair | 88027.8 | 88027.8 | 9 | 477.795 | 184.237 | 9780.87 | 9780.87 | ...de stratigraphies = default; ...de matériaux et couleurs = Ivoire clair; ...de matériaux et couleurs - 1 = Ivoire clair; ...de matériaux et couleurs - 2 = Ivoire clair
Enveloppe 767132 | Rez-de-chaussée | Enveloppe | 767132 | 366 | 9000 | 1977773087 | 1977773087 | 1 | 0 | 1097 | 03 | Rez-de-chaussée | no | rectangle | 138.537 | 477.795 | 0.0128504 | 0.0151137 | 477.795 | 180.015 | HAUT Rez-de-chaussée (Niveau 1 2343) | 0.0128504 | <aucun> | Rez-de-chaussée (Rez-de-chaussée 1047) | <aucun> | 138.5 | 138.5 | 477.8 | 477.8 | 1200 | 1200 | 1200 | 66200 | 600000 | Ivoire clair | Ivoire clair | 595731 | 230150 | 9 | 477.795 | 1246.83 | 66192.3 | 25572.3 | ...de stratigraphies = default; ...de matériaux et couleurs = Ivoire clair; ...de matériaux et couleurs - 1 = Ivoire clair; ...de matériaux et couleurs - 2 = Ivoire clair
Enveloppe 767345 | Rez-de-chaussée | Enveloppe | 767345 | 366 | 9000 | 1977773087 | 1977773087 | 1 | 0 | 1098 | 03 | Rez-de-chaussée | no | rectangle | 111.669 | 477.795 | 0.0128504 | 179.993 | 477.795 | 359.993 | HAUT Rez-de-chaussée (Niveau 1 2343) | 0.0128504 | <aucun> | Rez-de-chaussée (Rez-de-chaussée 1047) | <aucun> | 111.7 | 111.7 | 477.8 | 477.8 | 1000 | 1000 | 1000 | 53400 | 480000 | Ivoire clair | Ivoire clair | 480195 | 480195 | 9 | 477.795 | 1005.02 | 53355 | 53355 | ...de stratigraphies = default; ...de matériaux et couleurs = Ivoire clair; ...de matériaux et couleurs - 1 = Ivoire clair; ...de matériaux et couleurs - 2 = Ivoire clair
Enveloppe 719231 | Rez-de-chaussée | Enveloppe | 719231 | 366 | 9000 | 1977773087 | 1977773087 | 0 | 0 | 1048 | 03 | Rez-de-chaussée | no | rectangle | 38 | 477.795 | 0.0128504 | 0.412211 | 477.795 | 180.412 | HAUT Rez-de-chaussée (Niveau 1 2343) | 0.0128504 | <aucun> | Rez-de-chaussée (Rez-de-chaussée 1047) | <aucun> | 38 | 38 | 477.8 | 477.8 | 300 | 300 | 300 | 18200 | 160000 | Ivoire clair | Ivoire clair | 163406 | 163406 | 9 | 477.795 | 342 | 18156.2 | 18156.2 | ...de stratigraphies = default; ...de matériaux et couleurs = Ivoire clair; ...de matériaux et couleurs - 1 = Ivoire clair; ...de matériaux et couleurs - 2 = Ivoire clair
Enveloppe 719262 | Rez-de-chaussée | Enveloppe | 719262 | 366 | 9000 | 1977773087 | 1977773087 | 0 | 0 | 1049 | 03 | Rez-de-chaussée | no | rectangle | 44.0447 | 477.795 | 0.0128504 | 174.869 | 477.795 | 354.869 | HAUT Rez-de-chaussée (Niveau 1 2343) | 0.0128504 | <aucun> | Rez-de-chaussée (Rez-de-chaussée 1047) | <aucun> | 44 | 44 | 477.8 | 477.8 | 400 | 400 | 400 | 21000 | 190000 | Ivoire clair | Ivoire clair | 189399 | 189399 | 9 | 477.795 | 396.402 | 21044.4 | 21044.4 | ...de stratigraphies = default; ...de matériaux et couleurs = Ivoire clair; ...de matériaux et couleurs - 1 = Ivoire clair; ...de matériaux et couleurs - 2 = Ivoire clair
Enveloppe 720799 | Rez-de-chaussée | Enveloppe | 720799 | 366 | 9000 | 1977773087 | 1977773087 | 0 | 0 | 1054 | 03 | Rez-de-chaussée | no | rectangle | 69.4074 | 477.795 | 0.0128504 | 89.8622 | 477.795 | 269.862 | HAUT Rez-de-chaussée (Niveau 1 2343) | 0.0128504 | <aucun> | Rez-de-chaussée (Rez-de-chaussée 1047) | <aucun> | 69.4 | 69.4 | 477.8 | 477.8 | 600 | 600 | 600 | 33200 | 300000 | Ivoire clair | Ivoire clair | 298463 | 298463 | 9 | 477.795 | 624.666 | 33162.5 | 33162.5 | ...de stratigraphies = default; ...de matériaux et couleurs = Ivoire clair; ...de matériaux et couleurs - 1 = Ivoire clair; ...de matériaux et couleurs - 2 = Ivoire clair
Enveloppe 719893 | Rez-de-chaussée | Enveloppe | 719893 | 366 | 9000 | 1977773087 | 1977773087 | 0 | 0 | 1052 | 03 | Rez-de-chaussée | no | rectangle | 41.7273 | 477.795 | 0.0128504 | 2.40709 | 477.795 | 182.407 | HAUT Rez-de-chaussée (Niveau 1 2343) | 0.0128504 | <aucun> | Rez-de-chaussée (Rez-de-chaussée 1047) | <aucun> | 41.7 | 41.7 | 477.8 | 477.8 | 400 | 400 | 400 | 19900 | 180000 | Ivoire clair | Ivoire clair | 179434 | 179434 | 9 | 477.795 | 375.546 | 19937.1 | 19937.1 | ...de stratigraphies = default; ...de matériaux et couleurs = Ivoire clair; ...de matériaux et couleurs - 1 = Ivoire clair; ...de matériaux et couleurs - 2 = Ivoire clair
Enveloppe 673099 | Rez-de-chaussée | Enveloppe | 673099 | 366 | 9000 | 1977773087 | 1977773087 | 0 | 0 | 1037 | 03 | Rez-de-chaussée | no | rectangle | 171.952 | 477.795 | 0.0128504 | 90.6336 | 477.795 | 270.634 | HAUT Rez-de-chaussée (Niveau 1 2343) | 0.0128504 | <aucun> | Rez-de-chaussée (Rez-de-chaussée 1047) | <aucun> | 172 | 172 | 477.8 | 477.8 | 1500 | 1500 | 1500 | 82200 | 740000 | Ivoire clair | Ivoire clair | 739421 | 739421 | 9 | 477.795 | 1547.57 | 82157.9 | 82157.9 | ...de stratigraphies = default; ...de matériaux et couleurs = Ivoire clair; ...de matériaux et couleurs - 1 = Ivoire clair; ...de matériaux et couleurs - 2 = Ivoire clair
Enveloppe 673150 | Rez-de-chaussée | Enveloppe | 673150 | 366 | 9000 | 1977773087 | 1977773087 | 0 | 0 | 1038 | 03 | Rez-de-chaussée | no | rectangle | 254.447 | 477.795 | 0.0128504 | 0.649835 | 477.795 | 180.65 | HAUT Rez-de-chaussée (Niveau 1 2343) | 0.0128504 | <aucun> | Rez-de-chaussée (Rez-de-chaussée 1047) | <aucun> | 254.4 | 254.4 | 477.8 | 477.8 | 2300 | 2300 | 2300 | 121600 | 1090000 | Ivoire clair | Ivoire clair | 1094162 | 1094162 | 9 | 477.795 | 2290.02 | 121574 | 121574 | ...de stratigraphies = default; ...de matériaux et couleurs = Ivoire clair; ...de matériaux et couleurs - 1 = Ivoire clair; ...de matériaux et couleurs - 2 = Ivoire clair
Enveloppe 709104 | Rez-de-chaussée | Enveloppe | 709104 | 366 | 9000 | 1977773087 | 1977773087 | 0 | 1 | 1044 | 03 | Rez-de-chaussée | no | rectangle | 166.455 | 477.795 | 0.0128504 | 90.3486 | 477.795 | 270.349 | HAUT Rez-de-chaussée (Niveau 1 2343) | 0.0128504 | <aucun> | Rez-de-chaussée (Rez-de-chaussée 1047) | <aucun> | 166.5 | 166.5 | 477.8 | 477.8 | 1500 | 1500 | 1500 | 79600 | 720000 | Ivoire clair | Ivoire clair | 715784 | 384722 | 9 | 477.795 | 1498.1 | 79531.6 | 42746.9 | ...de stratigraphies = default; ...de matériaux et couleurs = Ivoire clair; ...de matériaux et couleurs - 1 = Ivoire clair; ...de matériaux et couleurs - 2 = Ivoire clair
Enveloppe 709039 | Rez-de-chaussée | Enveloppe | 709039 | 366 | 9000 | 1977773087 | 1977773087 | 0 | 1 | 1043 | 03 | Rez-de-chaussée | no | rectangle | 40.8687 | 477.795 | 0.0128504 | 90.7523 | 477.795 | 270.752 | HAUT Rez-de-chaussée (Niveau 1 2343) | 0.0128504 | <aucun> | Rez-de-chaussée (Rez-de-chaussée 1047) | <aucun> | 40.9 | 40.9 | 477.8 | 477.8 | 400 | 400 | 400 | 19500 | 180000 | Ivoire clair | Ivoire clair | 175742 | 175742 | 9 | 477.795 | 367.818 | 19526.9 | 19526.9 | ...de stratigraphies = default; ...de matériaux et couleurs = Ivoire clair; ...de matériaux et couleurs - 1 = Ivoire clair; ...de matériaux et couleurs - 2 = Ivoire clair
Enveloppe 721798 | Rez-de-chaussée | Enveloppe | 721798 | 366 | 9000 | 1977773087 | 1977773087 | 0 | 0 | 1058 | 03 | Rez-de-chaussée | no | rectangle | 30.4075 | 477.795 | 0.0128504 | 2.16949 | 477.795 | 182.169 | HAUT Rez-de-chaussée (Niveau 1 2343) | 0.0128504 | <aucun> | Rez-de-chaussée (Rez-de-chaussée 1047) | <aucun> | 30.4 | 30.4 | 477.8 | 477.8 | 300 | 300 | 300 | 14500 | 130000 | Ivoire clair | Ivoire clair | 130757 | 130757 | 9 | 477.795 | 273.667 | 14528.6 | 14528.6 | ...de stratigraphies = default; ...de matériaux et couleurs = Ivoire clair; ...de matériaux et couleurs - 1 = Ivoire clair; ...de matériaux et couleurs - 2 = Ivoire clair
Enveloppe 720894 | Rez-de-chaussée | Enveloppe | 720894 | 366 | 9000 | 1977773087 | 1977773087 | 0 | 0 | 1055 | 03 | Rez-de-chaussée | no | rectangle | 29.5642 | 477.795 | 0.0128504 | 171.724 | 477.795 | 351.724 | HAUT Rez-de-chaussée (Niveau 1 2343) | 0.0128504 | <aucun> | Rez-de-chaussée (Rez-de-chaussée 1047) | <aucun> | 29.6 | 29.6 | 477.8 | 477.8 | 300 | 300 | 300 | 14100 | 130000 | Ivoire clair | Ivoire clair | 127131 | 127131 | 9 | 477.795 | 266.078 | 14125.6 | 14125.6 | ...de stratigraphies = default; ...de matériaux et couleurs = Ivoire clair; ...de matériaux et couleurs - 1 = Ivoire clair; ...de matériaux et couleurs - 2 = Ivoire clair
Enveloppe 720961 | Rez-de-chaussée | Enveloppe | 720961 | 366 | 9000 | 1977773087 | 1977773087 | 1 | 0 | 1056 | 03 | Rez-de-chaussée | no | rectangle | 104.517 | 477.795 | 0.0128504 | 90.5209 | 477.795 | 270.521 | HAUT Rez-de-chaussée (Niveau 1 2343) | 0.0128504 | <aucun> | Rez-de-chaussée (Rez-de-chaussée 1047) | <aucun> | 104.5 | 104.5 | 477.8 | 477.8 | 900 | 900 | 900 | 49900 | 450000 | Ivoire clair | Ivoire clair | 449440 | 275333 | 9 | 477.795 | 940.654 | 49937.8 | 30592.5 | ...de stratigraphies = default; ...de matériaux et couleurs = Ivoire clair; ...de matériaux et couleurs - 1 = Ivoire clair; ...de matériaux et couleurs - 2 = Ivoire clair
Enveloppe 770964 | Rez-de-chaussée | Enveloppe | 770964 | 366 | 9000 | 1977773087 | 1977773087 | 1 | 0 | 1110 | 03 | Rez-de-chaussée | no | rectangle | 179.259 | 477.795 | 0.0128504 | 179.477 | 477.795 | 359.477 | HAUT Rez-de-chaussée (Niveau 1 2343) | 0.0128504 | <aucun> | Rez-de-chaussée (Rez-de-chaussée 1047) | <aucun> | 179.3 | 179.3 | 477.8 | 477.8 | 1600 | 1600 | 1600 | 85700 | 770000 | Ivoire clair | Ivoire clair | 770842 | 770842 | 9 | 477.795 | 1613.33 | 85649.1 | 85649.1 | ...de stratigraphies = default; ...de matériaux et couleurs = Ivoire clair; ...de matériaux et couleurs - 1 = Ivoire clair; ...de matériaux et couleurs - 2 = Ivoire clair
Enveloppe 1528099 | Rez-de-chaussée | Enveloppe | 1528099 | 366 | 9000 | 1977773087 | 1977773087 | 0 | 1 | 1161 | 03 | Rez-de-chaussée | no | rectangle | 22.7007 | 477.795 | 0.0128504 | 90.5287 | 477.795 | 270.529 | HAUT Rez-de-chaussée (Niveau 1 2343) | 0.0128504 | <aucun> | Rez-de-chaussée (Rez-de-chaussée 1047) | <aucun> | 22.7 | 22.7 | 477.8 | 477.8 | 200 | 200 | 200 | 10800 | 100000 | Ivoire clair | Ivoire clair | 97616.5 | 97616.5 | 9 | 477.795 | 204.306 | 10846.3 | 10846.3 | ...de stratigraphies = default; ...de matériaux et couleurs = Ivoire clair; ...de matériaux et couleurs - 1 = Ivoire clair; ...de matériaux et couleurs - 2 = Ivoire clair
Enveloppe 954645 | Rez-de-chaussée | Enveloppe | 954645 | 366 | 9000 | 1977773087 | 1977773087 | 0 | 0 | 1143 | 03 | Rez-de-chaussée | yes | rectangle | 105.302 | 653.91 | 200 | 90.2887 | 653.91 | 270.289 | HAUT Niveau 1 (Niveau 2 13545) | 8.88178e-12 | <aucun> | Rez-de-chaussée (Rez-de-chaussée 1047) | <aucun> | 105.3 | 105.3 | 653.9 | 653.9 | 900 | 900 | 900 | 68900 | 620000 | Ivoire clair | Ivoire clair | 619722 | 202249 | 9 | 653.91 | 947.716 | 68857.9 | 22472.2 | ...de stratigraphies = default; ...de matériaux et couleurs = Ivoire clair; ...de matériaux et couleurs - 1 = Ivoire clair; ...de matériaux et couleurs - 2 = Ivoire clair
Enveloppe 955886 | Rez-de-chaussée | Enveloppe | 955886 | 366 | 9000 | 1977773087 | 1977773087 | 1 | 0 | 1144 | 03 | Rez-de-chaussée | no | rectangle | 31.1392 | 653.91 | 200 | 90.2887 | 653.91 | 270.289 | HAUT Niveau 1 (Niveau 2 13545) | 1.06581e-11 | <aucun> | Rez-de-chaussée (Rez-de-chaussée 1047) | <aucun> | 31.1 | 31.1 | 653.9 | 653.9 | 300 | 300 | 300 | 20300 | 180000 | Ivoire clair | Ivoire clair | 183260 | 183260 | 9 | 653.91 | 280.253 | 20362.2 | 20362.2 | ...de stratigraphies = default; ...de matériaux et couleurs = Ivoire clair; ...de matériaux et couleurs - 1 = Ivoire clair; ...de matériaux et couleurs - 2 = Ivoire clair
Enveloppe 672947 | Rez-de-chaussée | Enveloppe | 672947 | 366 | 9000 | 1977773087 | 1977773087 | 0 | 0 | 1036 | 03 | Rez-de-chaussée | no | rectangle | 41.173 | 477.795 | 0.0128504 | 6.03278 | 477.795 | 186.033 | HAUT Rez-de-chaussée (Niveau 1 2343) | 0.0128504 | <aucun> | Rez-de-chaussée (Rez-de-chaussée 1047) | <aucun> | 41.2 | 41.2 | 477.8 | 477.8 | 400 | 400 | 400 | 19700 | 180000 | Ivoire clair | Ivoire clair | 177050 | 177050 | 9 | 477.795 | 370.557 | 19672.2 | 19672.2 | ...de stratigraphies = default; ...de matériaux et couleurs = Ivoire clair; ...de matériaux et couleurs - 1 = Ivoire clair; ...de matériaux et couleurs - 2 = Ivoire clair
Enveloppe 668042 | Rez-de-chaussée | Enveloppe | 668042 | 366 | 9000 | 1977773087 | 1977773087 | 0 | 0 | 1011 | 03 | Rez-de-chaussée | no | rectangle | 149.058 | 477.795 | 0.0128504 | 90.1563 | 477.795 | 270.156 | HAUT Rez-de-chaussée (Niveau 1 2343) | 0.0128504 | <aucun> | Rez-de-chaussée (Rez-de-chaussée 1047) | <aucun> | 149.1 | 149.1 | 477.8 | 477.8 | 1300 | 1300 | 1300 | 71200 | 640000 | Ivoire clair | Ivoire clair | 640972 | 290296 | 9 | 477.795 | 1341.52 | 71219.1 | 32255.1 | ...de stratigraphies = default; ...de matériaux et couleurs = Ivoire clair; ...de matériaux et couleurs - 1 = Ivoire clair; ...de matériaux et couleurs - 2 = Ivoire clair
Enveloppe 668499 | Rez-de-chaussée | Enveloppe | 668499 | 366 | 9000 | 1977773087 | 1977773087 | 1 | 0 | 1012 | 03 | Rez-de-chaussée | no | rectangle | 37.4825 | 477.795 | 0.0128504 | 85.9702 | 477.795 | 265.97 | HAUT Rez-de-chaussée (Niveau 1 2343) | 0.0128504 | <aucun> | Rez-de-chaussée (Rez-de-chaussée 1047) | <aucun> | 37.5 | 37.5 | 477.8 | 477.8 | 300 | 300 | 300 | 17900 | 160000 | Ivoire clair | Ivoire clair | 161181 | 161181 | 9 | 477.795 | 337.343 | 17909 | 17909 | ...de stratigraphies = default; ...de matériaux et couleurs = Ivoire clair; ...de matériaux et couleurs - 1 = Ivoire clair; ...de matériaux et couleurs - 2 = Ivoire clair
Enveloppe 667974 | Rez-de-chaussée | Enveloppe | 667974 | 366 | 9000 | 1977773087 | 1977773087 | 1 | 0 | 1009 | 03 | Rez-de-chaussée | no | rectangle | 122.711 | 477.795 | 0.0128504 | 90.1668 | 477.795 | 270.167 | HAUT Rez-de-chaussée (Niveau 1 2343) | 0.0128504 | <aucun> | Rez-de-chaussée (Rez-de-chaussée 1047) | <aucun> | 122.7 | 122.7 | 477.8 | 477.8 | 1100 | 1100 | 1100 | 58600 | 530000 | Ivoire clair | Ivoire clair | 527677 | 527677 | 9 | 477.795 | 1104.4 | 58630.8 | 58630.8 | ...de stratigraphies = default; ...de matériaux et couleurs = Ivoire clair; ...de matériaux et couleurs - 1 = Ivoire clair; ...de matériaux et couleurs - 2 = Ivoire clair
Enveloppe 668041 | Rez-de-chaussée | Enveloppe | 668041 | 366 | 9000 | 1977773087 | 1977773087 | 1 | 0 | 1010 | 03 | Rez-de-chaussée | no | rectangle | 26.3018 | 477.795 | 0.0128504 | 8.90201 | 477.795 | 188.902 | HAUT Rez-de-chaussée (Niveau 1 2343) | 0.0128504 | <aucun> | Rez-de-chaussée (Rez-de-chaussée 1047) | <aucun> | 26.3 | 26.3 | 477.8 | 477.8 | 200 | 200 | 200 | 12600 | 110000 | Ivoire clair | Ivoire clair | 113102 | 113102 | 9 | 477.795 | 236.717 | 12566.9 | 12566.9 | ...de stratigraphies = default; ...de matériaux et couleurs = Ivoire clair; ...de matériaux et couleurs - 1 = Ivoire clair; ...de matériaux et couleurs - 2 = Ivoire clair
Enveloppe 668703 | Rez-de-chaussée | Enveloppe | 668703 | 366 | 9000 | 1977773087 | 1977773087 | 1 | 0 | 1013 | 03 | Rez-de-chaussée | no | rectangle | 93.2987 | 477.795 | 0.0128504 | 0.212577 | 477.795 | 180.213 | HAUT Rez-de-chaussée (Niveau 1 2343) | 0.0128504 | <aucun> | Rez-de-chaussée (Rez-de-chaussée 1047) | <aucun> | 93.3 | 93.3 | 477.8 | 477.8 | 800 | 800 | 800 | 44600 | 400000 | Ivoire clair | Ivoire clair | 401199 | 401199 | 9 | 477.795 | 839.689 | 44577.7 | 44577.7 | ...de stratigraphies = default; ...de matériaux et couleurs = Ivoire clair; ...de matériaux et couleurs - 1 = Ivoire clair; ...de matériaux et couleurs - 2 = Ivoire clair
Enveloppe 668917 | Rez-de-chaussée | Enveloppe | 668917 | 366 | 9000 | 1977773087 | 1977773087 | 1 | 0 | 1016 | 03 | Rez-de-chaussée | no | rectangle | 129.108 | 477.795 | 0.0128504 | 0.212577 | 477.795 | 180.213 | HAUT Rez-de-chaussée (Niveau 1 2343) | 0.0128504 | <aucun> | Rez-de-chaussée (Rez-de-chaussée 1047) | <aucun> | 129.1 | 129.1 | 477.8 | 477.8 | 1200 | 1200 | 1200 | 61700 | 560000 | Ivoire clair | Ivoire clair | 555185 | 555185 | 9 | 477.795 | 1161.97 | 61687.2 | 61687.2 | ...de stratigraphies = default; ...de matériaux et couleurs = Ivoire clair; ...de matériaux et couleurs - 1 = Ivoire clair; ...de matériaux et couleurs - 2 = Ivoire clair
Enveloppe 668972 | Rez-de-chaussée | Enveloppe | 668972 | 366 | 9000 | 1977773087 | 1977773087 | 1 | 0 | 1017 | 03 | Rez-de-chaussée | no | rectangle | 37.664 | 477.795 | 0.0128504 | 85.078 | 477.795 | 265.078 | HAUT Rez-de-chaussée (Niveau 1 2343) | 0.0128504 | <aucun> | Rez-de-chaussée (Rez-de-chaussée 1047) | <aucun> | 37.7 | 37.7 | 477.8 | 477.8 | 300 | 300 | 300 | 18000 | 160000 | Ivoire clair | Ivoire clair | 161961 | 161961 | 9 | 477.795 | 338.976 | 17995.7 | 17995.7 | ...de stratigraphies = default; ...de matériaux et couleurs = Ivoire clair; ...de matériaux et couleurs - 1 = Ivoire clair; ...de matériaux et couleurs - 2 = Ivoire clair
Enveloppe 668710 | Rez-de-chaussée | Enveloppe | 668710 | 366 | 9000 | 1977773087 | 1977773087 | 0 | 0 | 1014 | 03 | Rez-de-chaussée | no | rectangle | 38.5679 | 477.795 | 0.0128504 | 98.5839 | 477.795 | 278.584 | HAUT Rez-de-chaussée (Niveau 1 2343) | 0.0128504 | <aucun> | Rez-de-chaussée (Rez-de-chaussée 1047) | <aucun> | 38.6 | 38.6 | 477.8 | 477.8 | 300 | 300 | 300 | 18400 | 170000 | Ivoire clair | Ivoire clair | 165848 | 165848 | 9 | 477.795 | 347.111 | 18427.6 | 18427.6 | ...de stratigraphies = default; ...de matériaux et couleurs = Ivoire clair; ...de matériaux et couleurs - 1 = Ivoire clair; ...de matériaux et couleurs - 2 = Ivoire clair
Enveloppe 668711 | Rez-de-chaussée | Enveloppe | 668711 | 366 | 9000 | 1977773087 | 1977773087 | 0 | 0 | 1015 | 03 | Rez-de-chaussée | no | rectangle | 134.987 | 477.795 | 0.0128504 | 0.213787 | 477.795 | 180.214 | HAUT Rez-de-chaussée (Niveau 1 2343) | 0.0128504 | <aucun> | Rez-de-chaussée (Rez-de-chaussée 1047) | <aucun> | 135 | 135 | 477.8 | 477.8 | 1200 | 1200 | 1200 | 64500 | 580000 | Ivoire clair | Ivoire clair | 580466 | 163787 | 9 | 477.795 | 1214.88 | 64496.2 | 18198.6 | ...de stratigraphies = default; ...de matériaux et couleurs = Ivoire clair; ...de matériaux et couleurs - 1 = Ivoire clair; ...de matériaux et couleurs - 2 = Ivoire clair
Enveloppe 666600 | Rez-de-chaussée | Enveloppe | 666600 | 366 | 9000 | 1977773087 | 1977773087 | 1 | 0 | 1002 | 03 | Rez-de-chaussée | no | rectangle | 36.9386 | 477.795 | 0.0128504 | 85.3839 | 477.795 | 265.384 | HAUT Rez-de-chaussée (Niveau 1 2343) | 0.0128504 | <aucun> | Rez-de-chaussée (Rez-de-chaussée 1047) | <aucun> | 36.9 | 36.9 | 477.8 | 477.8 | 300 | 300 | 300 | 17600 | 160000 | Ivoire clair | Ivoire clair | 158842 | 158842 | 9 | 477.795 | 332.448 | 17649.1 | 17649.1 | ...de stratigraphies = default; ...de matériaux et couleurs = Ivoire clair; ...de matériaux et couleurs - 1 = Ivoire clair; ...de matériaux et couleurs - 2 = Ivoire clair
Enveloppe 666959 | Rez-de-chaussée | Enveloppe | 666959 | 366 | 9000 | 1977773087 | 1977773087 | 1 | 0 | 1003 | 03 | Rez-de-chaussée | no | rectangle | 183.629 | 477.795 | 0.0128504 | 0.342193 | 477.795 | 180.342 | HAUT Rez-de-chaussée (Niveau 1 2343) | 0.0128504 | <aucun> | Rez-de-chaussée (Rez-de-chaussée 1047) | <aucun> | 183.6 | 183.6 | 477.8 | 477.8 | 1700 | 1700 | 1700 | 87700 | 790000 | Ivoire clair | Ivoire clair | 789632 | 789632 | 9 | 477.795 | 1652.66 | 87736.9 | 87736.9 | ...de stratigraphies = default; ...de matériaux et couleurs = Ivoire clair; ...de matériaux et couleurs - 1 = Ivoire clair; ...de matériaux et couleurs - 2 = Ivoire clair
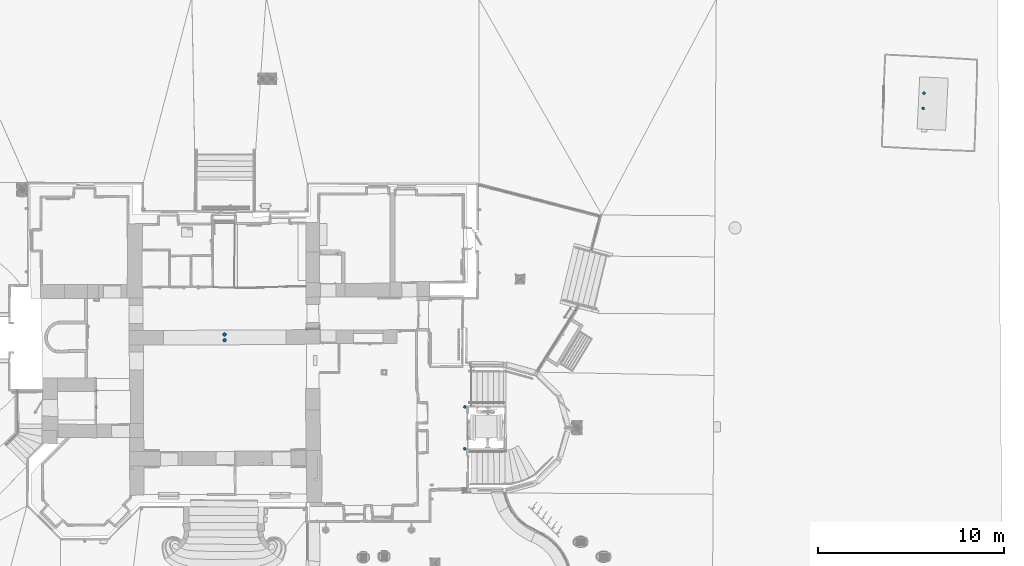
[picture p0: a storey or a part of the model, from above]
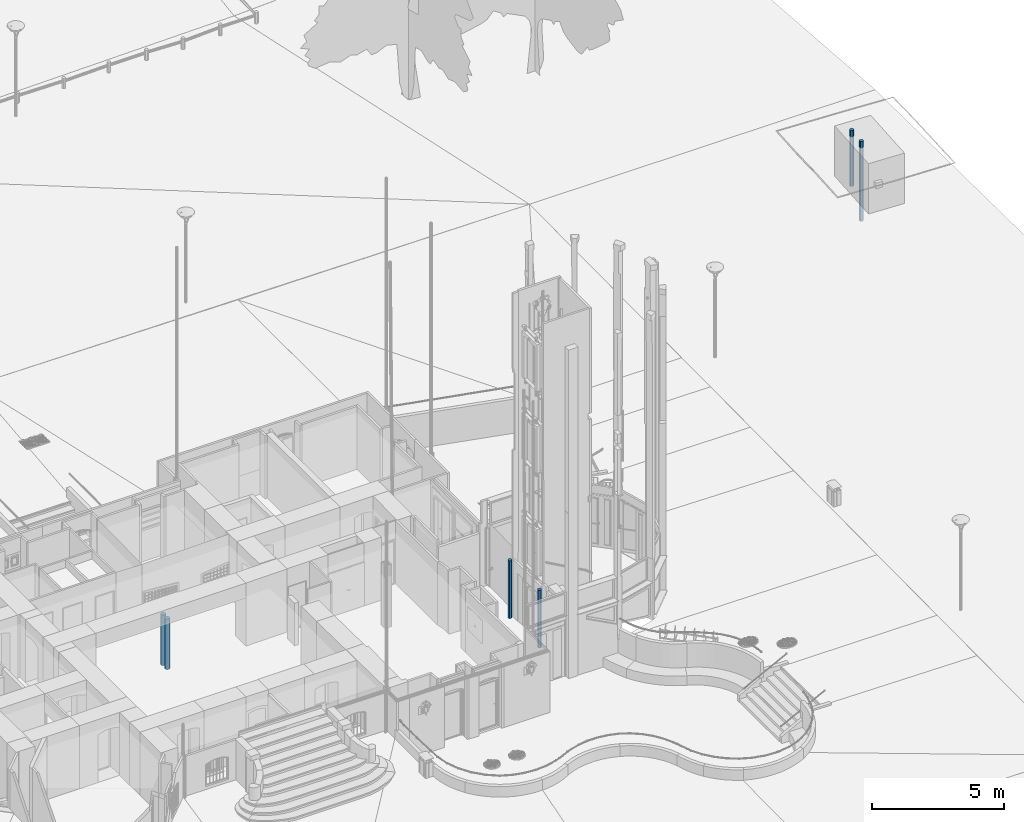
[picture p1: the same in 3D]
Properties of the parts of a building model (IFC2X3), part 31 of 37

# IfcWallStandardCase: default 90 (499)
Name | In | Description | __RECOGNIZE__, ID = IFC_Pset_Caractéristiques, ID | TPLG | TPLG_OD | 0, Crc | 1, Crc = 2, Crc | Alignment | ExternalFace | Numérotation | Numéro niveau | Titre niveau | Épaisseur VARIABLE | Forme en Élévation | Longueur (cm) = NominalLength (cm) | IFC_Pset_Géométrie, Hauteur (cm) = IFC_Pset_Géométrie_P1 (POINT initial), Hauteur (cm) | IFC_Pset_Géométrie, Cote (cm) = IFC_Pset_Géométrie_P1 (POINT initial), Cote (cm) = IFC_Pset_Géométrie_P2 (POINT final), Cote (cm) = IFC_Pset_Système de Référence Altimétrique_INFÉRIEUR, delta (cm) = IFC_Pset_Système de Référence Altimétrique_INFÉRIEUR, delta (P1) (cm) = IFC_Pset_Système de Référence Altimétrique_INFÉRIEUR, delta (P2) (cm) | IFC_Pset_Géométrie_P1 (POINT initial), Angle XY (deg) | IFC_Pset_Géométrie_P2 (POINT final), Hauteur (cm) | IFC_Pset_Géométrie_P2 (POINT final), Angle XY (deg) | IFC_Pset_Système de Référence Altimétrique_SUPÉRIEUR, NIVEAU | IFC_Pset_Système de Référence Altimétrique_SUPÉRIEUR, delta (cm) = IFC_Pset_Système de Référence Altimétrique_SUPÉRIEUR, delta (P1) (cm) = IFC_Pset_Système de Référence Altimétrique_SUPÉRIEUR, delta (P2) (cm) | IFC_Pset_Système de Référence Altimétrique_SUPÉRIEUR, sous Niveau | IFC_Pset_Système de Référence Altimétrique_INFÉRIEUR, NIVEAU | IFC_Pset_Système de Référence Altimétrique_INFÉRIEUR, sous Niveau | Longueur Pied (cm) | Longueur Tête (cm) | Hauteur Maximale (cm) | Hauteur Minimale (cm) | Surface en Plan (cm2) | Surface Pied (cm2) | Surface Tête (cm2) | Surface de la Paroi (cm2) | Volume (cm3) | Face gauche | Face droite = Face latérale | GrossVolume (cm3) | NetVolume (cm3) | NominalWidth (cm) | NominalHeight (cm) | GrossFootprintArea (cm2) = NetFootprintArea (cm2) | GrossSideArea (cm2) | NetSideArea (cm2) | Group
Enveloppe 665429 | Rez-de-chaussée | Enveloppe | 665429 | 366 | 9000 | 1977773087 | 1977773087 | 1 | 0 | 1000 | 03 | Rez-de-chaussée | no | rectangle | 30.039 | 477.795 | 0.0128504 | 172.545 | 477.795 | 352.545 | HAUT Rez-de-chaussée (Niveau 1 2343) | 0.0128504 | <aucun> | Rez-de-chaussée (Rez-de-chaussée 1047) | <aucun> | 30 | 30 | 477.8 | 477.8 | 300 | 300 | 300 | 14300 | 130000 | Ivoire clair | Ivoire clair | 129172 | 129172 | 9 | 477.795 | 270.351 | 14352.5 | 14352.5 | ...de stratigraphies = default; ...de matériaux et couleurs = Ivoire clair; ...de matériaux et couleurs - 1 = Ivoire clair; ...de matériaux et couleurs - 2 = Ivoire clair
Enveloppe 665604 | Rez-de-chaussée | Enveloppe | 665604 | 366 | 9000 | 1977773087 | 1977773087 | 1 | 0 | 1001 | 03 | Rez-de-chaussée | no | rectangle | 48.7921 | 477.795 | 0.0128504 | 90.194 | 477.795 | 270.194 | HAUT Rez-de-chaussée (Niveau 1 2343) | 0.0128504 | <aucun> | Rez-de-chaussée (Rez-de-chaussée 1047) | <aucun> | 48.8 | 48.8 | 477.8 | 477.8 | 400 | 400 | 400 | 23300 | 210000 | Ivoire clair | Ivoire clair | 209814 | 209814 | 9 | 477.795 | 439.129 | 23312.7 | 23312.7 | ...de stratigraphies = default; ...de matériaux et couleurs = Ivoire clair; ...de matériaux et couleurs - 1 = Ivoire clair; ...de matériaux et couleurs - 2 = Ivoire clair
Enveloppe 666967 | Rez-de-chaussée | Enveloppe | 666967 | 366 | 9000 | 1977773087 | 1977773087 | 1 | 0 | 1004 | 03 | Rez-de-chaussée | no | rectangle | 161.019 | 477.795 | 0.0128504 | 0.342193 | 477.795 | 180.342 | HAUT Rez-de-chaussée (Niveau 1 2343) | 0.0128504 | <aucun> | Rez-de-chaussée (Rez-de-chaussée 1047) | <aucun> | 161 | 161 | 477.8 | 477.8 | 1400 | 1400 | 1400 | 76900 | 690000 | Ivoire clair | Ivoire clair | 692407 | 692407 | 9 | 477.795 | 1449.17 | 76934.1 | 76934.1 | ...de stratigraphies = default; ...de matériaux et couleurs = Ivoire clair; ...de matériaux et couleurs - 1 = Ivoire clair; ...de matériaux et couleurs - 2 = Ivoire clair
Enveloppe 667678 | Rez-de-chaussée | Enveloppe | 667678 | 366 | 9000 | 1977773087 | 1977773087 | 1 | 0 | 1007 | 03 | Rez-de-chaussée | no | rectangle | 28.4728 | 477.795 | 0.0128504 | 174.681 | 477.795 | 354.681 | HAUT Rez-de-chaussée (Niveau 1 2343) | 0.0128504 | <aucun> | Rez-de-chaussée (Rez-de-chaussée 1047) | <aucun> | 28.5 | 28.5 | 477.8 | 477.8 | 300 | 300 | 300 | 13600 | 120000 | Ivoire clair | Ivoire clair | 122438 | 122438 | 9 | 477.795 | 256.255 | 13604.2 | 13604.2 | ...de stratigraphies = default; ...de matériaux et couleurs = Ivoire clair; ...de matériaux et couleurs - 1 = Ivoire clair; ...de matériaux et couleurs - 2 = Ivoire clair
Enveloppe 667856 | Rez-de-chaussée | Enveloppe | 667856 | 366 | 9000 | 1977773087 | 1977773087 | 1 | 0 | 1008 | 03 | Rez-de-chaussée | no | rectangle | 180.43 | 477.795 | 0.0128504 | 89.7293 | 477.795 | 269.729 | HAUT Rez-de-chaussée (Niveau 1 2343) | 0.0128504 | <aucun> | Rez-de-chaussée (Rez-de-chaussée 1047) | <aucun> | 180.4 | 180.4 | 477.8 | 477.8 | 1600 | 1600 | 1600 | 86200 | 780000 | Ivoire clair | Ivoire clair | 775876 | 775876 | 9 | 477.795 | 1623.87 | 86208.5 | 86208.5 | ...de stratigraphies = default; ...de matériaux et couleurs = Ivoire clair; ...de matériaux et couleurs - 1 = Ivoire clair; ...de matériaux et couleurs - 2 = Ivoire clair
Enveloppe 667195 | Rez-de-chaussée | Enveloppe | 667195 | 366 | 9000 | 1977773087 | 1977773087 | 0 | 0 | 1005 | 03 | Rez-de-chaussée | no | rectangle | 133.43 | 477.795 | 0.0128504 | 0.342805 | 477.795 | 180.343 | HAUT Rez-de-chaussée (Niveau 1 2343) | 0.0128504 | <aucun> | Rez-de-chaussée (Rez-de-chaussée 1047) | <aucun> | 133.4 | 133.4 | 477.8 | 477.8 | 1200 | 1200 | 1200 | 63700 | 570000 | Ivoire clair | Ivoire clair | 573768 | 215610 | 9 | 477.795 | 1200.87 | 63752 | 23956.7 | ...de stratigraphies = default; ...de matériaux et couleurs = Ivoire clair; ...de matériaux et couleurs - 1 = Ivoire clair; ...de matériaux et couleurs - 2 = Ivoire clair
Enveloppe 667464 | Rez-de-chaussée | Enveloppe | 667464 | 366 | 9000 | 1977773087 | 1977773087 | 0 | 0 | 1006 | 03 | Rez-de-chaussée | no | rectangle | 36.7857 | 477.795 | 0.0128504 | 97.4294 | 477.795 | 277.429 | HAUT Rez-de-chaussée (Niveau 1 2343) | 0.0128504 | <aucun> | Rez-de-chaussée (Rez-de-chaussée 1047) | <aucun> | 36.8 | 36.8 | 477.8 | 477.8 | 300 | 300 | 300 | 17600 | 160000 | Ivoire clair | Ivoire clair | 158184 | 158184 | 9 | 477.795 | 331.071 | 17576 | 17576 | ...de stratigraphies = default; ...de matériaux et couleurs = Ivoire clair; ...de matériaux et couleurs - 1 = Ivoire clair; ...de matériaux et couleurs - 2 = Ivoire clair
Enveloppe 671504 | Rez-de-chaussée | Enveloppe | 671504 | 366 | 9000 | 1977773087 | 1977773087 | 0 | 0 | 1029 | 03 | Rez-de-chaussée | no | rectangle | 146.864 | 477.795 | 0.0128504 | 0.264755 | 477.795 | 180.265 | HAUT Rez-de-chaussée (Niveau 1 2343) | 0.0128504 | <aucun> | Rez-de-chaussée (Rez-de-chaussée 1047) | <aucun> | 146.9 | 146.9 | 477.8 | 477.8 | 1300 | 1300 | 1300 | 70200 | 630000 | Ivoire clair | Ivoire clair | 631540 | 187639 | 9 | 477.795 | 1321.78 | 70171.1 | 20848.8 | ...de stratigraphies = default; ...de matériaux et couleurs = Ivoire clair; ...de matériaux et couleurs - 1 = Ivoire clair; ...de matériaux et couleurs - 2 = Ivoire clair
Enveloppe 671646 | Rez-de-chaussée | Enveloppe | 671646 | 366 | 9000 | 1977773087 | 1977773087 | 1 | 0 | 1030 | 03 | Rez-de-chaussée | no | rectangle | 26.384 | 477.795 | 0.0128504 | 85.5381 | 477.795 | 265.538 | HAUT Rez-de-chaussée (Niveau 1 2343) | 0.0128504 | <aucun> | Rez-de-chaussée (Rez-de-chaussée 1047) | <aucun> | 26.4 | 26.4 | 477.8 | 477.8 | 200 | 200 | 200 | 12600 | 110000 | Ivoire clair | Ivoire clair | 113455 | 113455 | 9 | 477.795 | 237.456 | 12606.2 | 12606.2 | ...de stratigraphies = default; ...de matériaux et couleurs = Ivoire clair; ...de matériaux et couleurs - 1 = Ivoire clair; ...de matériaux et couleurs - 2 = Ivoire clair
Enveloppe 670785 | Rez-de-chaussée | Enveloppe | 670785 | 366 | 9000 | 1977773087 | 1977773087 | 1 | 0 | 1027 | 03 | Rez-de-chaussée | no | rectangle | 215.683 | 477.795 | 0.0128504 | 0.264755 | 477.795 | 180.265 | HAUT Rez-de-chaussée (Niveau 1 2343) | 0.0128504 | <aucun> | Rez-de-chaussée (Rez-de-chaussée 1047) | <aucun> | 215.7 | 215.7 | 477.8 | 477.8 | 1900 | 1900 | 1900 | 103100 | 930000 | Ivoire clair | Ivoire clair | 927471 | 927471 | 9 | 477.795 | 1941.15 | 103052 | 103052 | ...de stratigraphies = default; ...de matériaux et couleurs = Ivoire clair; ...de matériaux et couleurs - 1 = Ivoire clair; ...de matériaux et couleurs - 2 = Ivoire clair
Enveloppe 671451 | Rez-de-chaussée | Enveloppe | 671451 | 366 | 9000 | 1977773087 | 1977773087 | 1 | 0 | 1028 | 03 | Rez-de-chaussée | no | rectangle | 37.8362 | 477.795 | 0.0128504 | 1.33347 | 477.795 | 181.333 | HAUT Rez-de-chaussée (Niveau 1 2343) | 0.0128504 | <aucun> | Rez-de-chaussée (Rez-de-chaussée 1047) | <aucun> | 37.8 | 37.8 | 477.8 | 477.8 | 300 | 300 | 300 | 18100 | 160000 | Ivoire clair | Ivoire clair | 162702 | 162702 | 9 | 477.795 | 340.526 | 18078 | 18078 | ...de stratigraphies = default; ...de matériaux et couleurs = Ivoire clair; ...de matériaux et couleurs - 1 = Ivoire clair; ...de matériaux et couleurs - 2 = Ivoire clair
Enveloppe 671854 | Rez-de-chaussée | Enveloppe | 671854 | 366 | 9000 | 1977773087 | 1977773087 | 0 | 0 | 1031 | 03 | Rez-de-chaussée | no | rectangle | 140.249 | 477.795 | 0.0128504 | 0.264755 | 477.795 | 180.265 | HAUT Rez-de-chaussée (Niveau 1 2343) | 0.0128504 | <aucun> | Rez-de-chaussée (Rez-de-chaussée 1047) | <aucun> | 140.2 | 140.2 | 477.8 | 477.8 | 1300 | 1300 | 1300 | 67000 | 600000 | Ivoire clair | Ivoire clair | 603092 | 207327 | 9 | 477.795 | 1262.24 | 67010.2 | 23036.3 | ...de stratigraphies = default; ...de matériaux et couleurs = Ivoire clair; ...de matériaux et couleurs - 1 = Ivoire clair; ...de matériaux et couleurs - 2 = Ivoire clair
Enveloppe 672747 | Rez-de-chaussée | Enveloppe | 672747 | 366 | 9000 | 1977773087 | 1977773087 | 1 | 0 | 1034 | 03 | Rez-de-chaussée | no | rectangle | 134.482 | 477.795 | 0.0128504 | 90.311 | 477.795 | 270.311 | HAUT Rez-de-chaussée (Niveau 1 2343) | 0.0128504 | <aucun> | Rez-de-chaussée (Rez-de-chaussée 1047) | <aucun> | 134.5 | 134.5 | 477.8 | 477.8 | 1200 | 1200 | 1200 | 64300 | 580000 | Ivoire clair | Ivoire clair | 578293 | 257863 | 9 | 477.795 | 1210.34 | 64254.8 | 28651.4 | ...de stratigraphies = default; ...de matériaux et couleurs = Ivoire clair; ...de matériaux et couleurs - 1 = Ivoire clair; ...de matériaux et couleurs - 2 = Ivoire clair
Enveloppe 672919 | Rez-de-chaussée | Enveloppe | 672919 | 366 | 9000 | 1977773087 | 1977773087 | 0 | 0 | 1035 | 03 | Rez-de-chaussée | no | rectangle | 174.091 | 477.795 | 0.0128504 | 90.3124 | 477.795 | 270.312 | HAUT Rez-de-chaussée (Niveau 1 2343) | 0.0128504 | <aucun> | Rez-de-chaussée (Rez-de-chaussée 1047) | <aucun> | 174.1 | 174.1 | 477.8 | 477.8 | 1600 | 1600 | 1600 | 83200 | 750000 | Ivoire clair | Ivoire clair | 748619 | 748619 | 9 | 477.795 | 1566.82 | 83179.9 | 83179.9 | ...de stratigraphies = default; ...de matériaux et couleurs = Ivoire clair; ...de matériaux et couleurs - 1 = Ivoire clair; ...de matériaux et couleurs - 2 = Ivoire clair
Enveloppe 672633 | Rez-de-chaussée | Enveloppe | 672633 | 366 | 9000 | 1977773087 | 1977773087 | 1 | 0 | 1032 | 03 | Rez-de-chaussée | no | rectangle | 224.989 | 477.795 | 0.0128504 | 0.264754 | 477.795 | 180.265 | HAUT Rez-de-chaussée (Niveau 1 2343) | 0.0128504 | <aucun> | Rez-de-chaussée (Rez-de-chaussée 1047) | <aucun> | 225 | 225 | 477.8 | 477.8 | 2000 | 2000 | 2000 | 107500 | 970000 | Ivoire clair | Ivoire clair | 967486 | 967486 | 9 | 477.795 | 2024.9 | 107498 | 107498 | ...de stratigraphies = default; ...de matériaux et couleurs = Ivoire clair; ...de matériaux et couleurs - 1 = Ivoire clair; ...de matériaux et couleurs - 2 = Ivoire clair
Enveloppe 672746 | Rez-de-chaussée | Enveloppe | 672746 | 366 | 9000 | 1977773087 | 1977773087 | 0 | 0 | 1033 | 03 | Rez-de-chaussée | no | rectangle | 40.2454 | 477.795 | 0.0128504 | 176.016 | 477.795 | 356.016 | HAUT Rez-de-chaussée (Niveau 1 2343) | 0.0128504 | <aucun> | Rez-de-chaussée (Rez-de-chaussée 1047) | <aucun> | 40.2 | 40.2 | 477.8 | 477.8 | 400 | 400 | 400 | 19200 | 170000 | Ivoire clair | Ivoire clair | 173062 | 173062 | 9 | 477.795 | 362.208 | 19229.1 | 19229.1 | ...de stratigraphies = default; ...de matériaux et couleurs = Ivoire clair; ...de matériaux et couleurs - 1 = Ivoire clair; ...de matériaux et couleurs - 2 = Ivoire clair
Enveloppe 669420 | Rez-de-chaussée | Enveloppe | 669420 | 366 | 9000 | 1977773087 | 1977773087 | 0 | 0 | 1020 | 03 | Rez-de-chaussée | no | rectangle | 210.685 | 477.795 | 0.0128504 | 0.213787 | 477.795 | 180.214 | HAUT Rez-de-chaussée (Niveau 1 2343) | 0.0128504 | <aucun> | Rez-de-chaussée (Rez-de-chaussée 1047) | <aucun> | 210.7 | 210.7 | 477.8 | 477.8 | 1900 | 1900 | 1900 | 100700 | 910000 | Ivoire clair | Ivoire clair | 905979 | 319403 | 9 | 477.795 | 1896.17 | 100664 | 35489.2 | ...de stratigraphies = default; ...de matériaux et couleurs = Ivoire clair; ...de matériaux et couleurs - 1 = Ivoire clair; ...de matériaux et couleurs - 2 = Ivoire clair
Enveloppe 669589 | Rez-de-chaussée | Enveloppe | 669589 | 366 | 9000 | 1977773087 | 1977773087 | 1 | 0 | 1021 | 03 | Rez-de-chaussée | no | rectangle | 129.428 | 477.795 | 0.0128504 | 0.176298 | 477.795 | 180.176 | HAUT Rez-de-chaussée (Niveau 1 2343) | 0.0128504 | <aucun> | Rez-de-chaussée (Rez-de-chaussée 1047) | <aucun> | 129.4 | 129.4 | 477.8 | 477.8 | 1200 | 1200 | 1200 | 61800 | 560000 | Ivoire clair | Ivoire clair | 556560 | 556560 | 9 | 477.795 | 1164.85 | 61840 | 61840 | ...de stratigraphies = default; ...de matériaux et couleurs = Ivoire clair; ...de matériaux et couleurs - 1 = Ivoire clair; ...de matériaux et couleurs - 2 = Ivoire clair
Enveloppe 669187 | Rez-de-chaussée | Enveloppe | 669187 | 366 | 9000 | 1977773087 | 1977773087 | 1 | 0 | 1018 | 03 | Rez-de-chaussée | no | rectangle | 70.8189 | 477.795 | 0.0128504 | 0.336177 | 477.795 | 180.336 | HAUT Rez-de-chaussée (Niveau 1 2343) | 0.0128504 | <aucun> | Rez-de-chaussée (Rez-de-chaussée 1047) | <aucun> | 70.8 | 70.8 | 477.8 | 477.8 | 600 | 600 | 600 | 33800 | 300000 | Ivoire clair | Ivoire clair | 304532 | 304532 | 9 | 477.795 | 637.37 | 33836.9 | 33836.9 | ...de stratigraphies = default; ...de matériaux et couleurs = Ivoire clair; ...de matériaux et couleurs - 1 = Ivoire clair; ...de matériaux et couleurs - 2 = Ivoire clair
Enveloppe 669265 | Rez-de-chaussée | Enveloppe | 669265 | 366 | 9000 | 1977773087 | 1977773087 | 0 | 0 | 1019 | 03 | Rez-de-chaussée | no | rectangle | 37.7982 | 477.795 | 0.0128504 | 95.1641 | 477.795 | 275.164 | HAUT Rez-de-chaussée (Niveau 1 2343) | 0.0128504 | <aucun> | Rez-de-chaussée (Rez-de-chaussée 1047) | <aucun> | 37.8 | 37.8 | 477.8 | 477.8 | 300 | 300 | 300 | 18100 | 160000 | Ivoire clair | Ivoire clair | 162538 | 162538 | 9 | 477.795 | 340.184 | 18059.8 | 18059.8 | ...de stratigraphies = default; ...de matériaux et couleurs = Ivoire clair; ...de matériaux et couleurs - 1 = Ivoire clair; ...de matériaux et couleurs - 2 = Ivoire clair
Enveloppe 669642 | Rez-de-chaussée | Enveloppe | 669642 | 366 | 9000 | 1977773087 | 1977773087 | 1 | 0 | 1022 | 03 | Rez-de-chaussée | no | rectangle | 38.8249 | 477.795 | 0.0128504 | 83.6607 | 477.795 | 263.661 | HAUT Rez-de-chaussée (Niveau 1 2343) | 0.0128504 | <aucun> | Rez-de-chaussée (Rez-de-chaussée 1047) | <aucun> | 38.8 | 38.8 | 477.8 | 477.8 | 300 | 300 | 300 | 18500 | 170000 | Ivoire clair | Ivoire clair | 166953 | 166953 | 9 | 477.795 | 349.424 | 18550.3 | 18550.3 | ...de stratigraphies = default; ...de matériaux et couleurs = Ivoire clair; ...de matériaux et couleurs - 1 = Ivoire clair; ...de matériaux et couleurs - 2 = Ivoire clair
Enveloppe 670679 | Rez-de-chaussée | Enveloppe | 670679 | 366 | 9000 | 1977773087 | 1977773087 | 1 | 0 | 1025 | 03 | Rez-de-chaussée | no | rectangle | 20 | 477.795 | 0.0128504 | 2.71484 | 477.795 | 182.715 | HAUT Rez-de-chaussée (Niveau 1 2343) | 0.0128504 | <aucun> | Rez-de-chaussée (Rez-de-chaussée 1047) | <aucun> | 20 | 20 | 477.8 | 477.8 | 200 | 200 | 200 | 9600 | 90000 | Ivoire clair | Ivoire clair | 86003.2 | 86003.2 | 9 | 477.795 | 180 | 9555.91 | 9555.91 | ...de stratigraphies = default; ...de matériaux et couleurs = Ivoire clair; ...de matériaux et couleurs - 1 = Ivoire clair; ...de matériaux et couleurs - 2 = Ivoire clair
Enveloppe 670733 | Rez-de-chaussée | Enveloppe | 670733 | 366 | 9000 | 1977773087 | 1977773087 | 1 | 0 | 1026 | 03 | Rez-de-chaussée | no | rectangle | 20 | 477.795 | 0.0128504 | 79.0649 | 477.795 | 259.065 | HAUT Rez-de-chaussée (Niveau 1 2343) | 0.0128504 | <aucun> | Rez-de-chaussée (Rez-de-chaussée 1047) | <aucun> | 20 | 20 | 477.8 | 477.8 | 200 | 200 | 200 | 9600 | 90000 | Ivoire clair | Ivoire clair | 86003.2 | 86003.2 | 9 | 477.795 | 180 | 9555.91 | 9555.91 | ...de stratigraphies = default; ...de matériaux et couleurs = Ivoire clair; ...de matériaux et couleurs - 1 = Ivoire clair; ...de matériaux et couleurs - 2 = Ivoire clair
Enveloppe 669856 | Rez-de-chaussée | Enveloppe | 669856 | 366 | 9000 | 1977773087 | 1977773087 | 0 | 0 | 1023 | 03 | Rez-de-chaussée | no | rectangle | 38.0503 | 477.795 | 0.0128504 | 97.0726 | 477.795 | 277.073 | HAUT Rez-de-chaussée (Niveau 1 2343) | 0.0128504 | <aucun> | Rez-de-chaussée (Rez-de-chaussée 1047) | <aucun> | 38.1 | 38.1 | 477.8 | 477.8 | 300 | 300 | 300 | 18200 | 160000 | Ivoire clair | Ivoire clair | 163622 | 163622 | 9 | 477.795 | 342.452 | 18180.2 | 18180.2 | ...de stratigraphies = default; ...de matériaux et couleurs = Ivoire clair; ...de matériaux et couleurs - 1 = Ivoire clair; ...de matériaux et couleurs - 2 = Ivoire clair
Enveloppe 669857 | Rez-de-chaussée | Enveloppe | 669857 | 366 | 9000 | 1977773087 | 1977773087 | 0 | 0 | 1024 | 03 | Rez-de-chaussée | no | rectangle | 135.171 | 477.795 | 0.0128504 | 0.213787 | 477.795 | 180.214 | HAUT Rez-de-chaussée (Niveau 1 2343) | 0.0128504 | <aucun> | Rez-de-chaussée (Rez-de-chaussée 1047) | <aucun> | 135.2 | 135.2 | 477.8 | 477.8 | 1200 | 1200 | 1200 | 64600 | 580000 | Ivoire clair | Ivoire clair | 581259 | 182738 | 9 | 477.795 | 1216.54 | 64584.3 | 20304.3 | ...de stratigraphies = default; ...de matériaux et couleurs = Ivoire clair; ...de matériaux et couleurs - 1 = Ivoire clair; ...de matériaux et couleurs - 2 = Ivoire clair
Enveloppe 665263 | Rez-de-chaussée | Enveloppe | 665263 | 366 | 9000 | 1977773087 | 1977773087 | 0 | 0 | 0999 | 03 | Rez-de-chaussée | no | rectangle | 103.127 | 477.795 | 0.0128504 | 90.1972 | 477.795 | 270.197 | HAUT Rez-de-chaussée (Niveau 1 2343) | 0.0128504 | <aucun> | Rez-de-chaussée (Rez-de-chaussée 1047) | <aucun> | 103.1 | 103.1 | 477.8 | 477.8 | 900 | 900 | 900 | 49300 | 440000 | Ivoire clair | Ivoire clair | 443461 | 243140 | 9 | 477.795 | 928.139 | 49273.4 | 27015.6 | ...de stratigraphies = default; ...de matériaux et couleurs = Ivoire clair; ...de matériaux et couleurs - 1 = Ivoire clair; ...de matériaux et couleurs - 2 = Ivoire clair
Enveloppe 664003 | Rez-de-chaussée | Enveloppe | 664003 | 366 | 9000 | 1977773087 | 1977773087 | 0 | 0 | 0992 | 03 | Rez-de-chaussée | no | rectangle | 129.904 | 477.795 | 0.0128504 | 135.721 | 477.795 | 315.721 | HAUT Rez-de-chaussée (Niveau 1 2343) | 0.0128504 | <aucun> | Rez-de-chaussée (Rez-de-chaussée 1047) | <aucun> | 129.9 | 129.9 | 477.8 | 477.8 | 1200 | 1200 | 1200 | 62100 | 560000 | Ivoire clair | Ivoire clair | 558608 | 227822 | 9 | 477.795 | 1169.14 | 62067.5 | 25313.6 | ...de stratigraphies = default; ...de matériaux et couleurs = Ivoire clair; ...de matériaux et couleurs - 1 = Ivoire clair; ...de matériaux et couleurs - 2 = Ivoire clair
Enveloppe 664477 | Rez-de-chaussée | Enveloppe | 664477 | 366 | 9000 | 1977773087 | 1977773087 | 0 | 0 | 0993 | 03 | Rez-de-chaussée | no | rectangle | 25.7673 | 477.795 | 0.0128504 | 90.3416 | 477.795 | 270.342 | HAUT Rez-de-chaussée (Niveau 1 2343) | 0.0128504 | <aucun> | Rez-de-chaussée (Rez-de-chaussée 1047) | <aucun> | 25.8 | 25.8 | 477.8 | 477.8 | 200 | 200 | 200 | 12300 | 110000 | Ivoire clair | Ivoire clair | 110804 | 110804 | 9 | 477.795 | 231.906 | 12311.5 | 12311.5 | ...de stratigraphies = default; ...de matériaux et couleurs = Ivoire clair; ...de matériaux et couleurs - 1 = Ivoire clair; ...de matériaux et couleurs - 2 = Ivoire clair
Enveloppe 663948 | Rez-de-chaussée | Enveloppe | 663948 | 366 | 9000 | 1977773087 | 1977773087 | 1 | 0 | 0990 | 03 | Rez-de-chaussée | no | rectangle | 30.2967 | 477.795 | 0.0128504 | 134.361 | 477.795 | 314.361 | HAUT Rez-de-chaussée (Niveau 1 2343) | 0.0128504 | <aucun> | Rez-de-chaussée (Rez-de-chaussée 1047) | <aucun> | 30.3 | 30.3 | 477.8 | 477.8 | 300 | 300 | 300 | 14500 | 130000 | Ivoire clair | Ivoire clair | 130281 | 130281 | 9 | 477.795 | 272.67 | 14475.6 | 14475.6 | ...de stratigraphies = default; ...de matériaux et couleurs = Ivoire clair; ...de matériaux et couleurs - 1 = Ivoire clair; ...de matériaux et couleurs - 2 = Ivoire clair
Enveloppe 664002 | Rez-de-chaussée | Enveloppe | 664002 | 366 | 9000 | 1977773087 | 1977773087 | 1 | 0 | 0991 | 03 | Rez-de-chaussée | no | rectangle | 35.0598 | 477.795 | 0.0128504 | 53.0404 | 477.795 | 233.04 | HAUT Rez-de-chaussée (Niveau 1 2343) | 0.0128504 | <aucun> | Rez-de-chaussée (Rez-de-chaussée 1047) | <aucun> | 35.1 | 35.1 | 477.8 | 477.8 | 300 | 300 | 300 | 16800 | 150000 | Ivoire clair | Ivoire clair | 150763 | 150763 | 9 | 477.795 | 315.539 | 16751.4 | 16751.4 | ...de stratigraphies = default; ...de matériaux et couleurs = Ivoire clair; ...de matériaux et couleurs - 1 = Ivoire clair; ...de matériaux et couleurs - 2 = Ivoire clair
Enveloppe 664554 | Rez-de-chaussée | Enveloppe | 664554 | 366 | 9000 | 1977773087 | 1977773087 | 1 | 0 | 0994 | 03 | Rez-de-chaussée | no | rectangle | 26.9976 | 477.795 | 0.0128504 | 0.350884 | 477.795 | 180.351 | HAUT Rez-de-chaussée (Niveau 1 2343) | 0.0128504 | <aucun> | Rez-de-chaussée (Rez-de-chaussée 1047) | <aucun> | 27 | 27 | 477.8 | 477.8 | 200 | 200 | 200 | 12900 | 120000 | Ivoire clair | Ivoire clair | 116094 | 116094 | 9 | 477.795 | 242.978 | 12899.3 | 12899.3 | ...de stratigraphies = default; ...de matériaux et couleurs = Ivoire clair; ...de matériaux et couleurs - 1 = Ivoire clair; ...de matériaux et couleurs - 2 = Ivoire clair
Enveloppe 664761 | Rez-de-chaussée | Enveloppe | 664761 | 366 | 9000 | 1977773087 | 1977773087 | 0 | 0 | 0997 | 03 | Rez-de-chaussée | no | rectangle | 27 | 477.795 | 0.0128504 | 0.341557 | 477.795 | 180.342 | HAUT Rez-de-chaussée (Niveau 1 2343) | 0.0128504 | <aucun> | Rez-de-chaussée (Rez-de-chaussée 1047) | <aucun> | 27 | 27 | 477.8 | 477.8 | 200 | 200 | 200 | 12900 | 120000 | Ivoire clair | Ivoire clair | 116104 | 116104 | 9 | 477.795 | 243 | 12900.5 | 12900.5 | ...de stratigraphies = default; ...de matériaux et couleurs = Ivoire clair; ...de matériaux et couleurs - 1 = Ivoire clair; ...de matériaux et couleurs - 2 = Ivoire clair
Enveloppe 665094 | Rez-de-chaussée | Enveloppe | 665094 | 366 | 9000 | 1977773087 | 1977773087 | 1 | 0 | 0998 | 03 | Rez-de-chaussée | no | rectangle | 52.6439 | 477.795 | 0.0128504 | 90.194 | 477.795 | 270.194 | HAUT Rez-de-chaussée (Niveau 1 2343) | 0.0128504 | <aucun> | Rez-de-chaussée (Rez-de-chaussée 1047) | <aucun> | 52.6 | 52.6 | 477.8 | 477.8 | 500 | 500 | 500 | 25100 | 230000 | Ivoire clair | Ivoire clair | 226377 | 226377 | 9 | 477.795 | 473.795 | 25153 | 25153 | ...de stratigraphies = default; ...de matériaux et couleurs = Ivoire clair; ...de matériaux et couleurs - 1 = Ivoire clair; ...de matériaux et couleurs - 2 = Ivoire clair
Enveloppe 664555 | Rez-de-chaussée | Enveloppe | 664555 | 366 | 9000 | 1977773087 | 1977773087 | 1 | 0 | 0995 | 03 | Rez-de-chaussée | no | rectangle | 142.152 | 477.795 | 0.0128504 | 90.3416 | 477.795 | 270.342 | HAUT Rez-de-chaussée (Niveau 1 2343) | 0.0128504 | <aucun> | Rez-de-chaussée (Rez-de-chaussée 1047) | <aucun> | 142.2 | 142.2 | 477.8 | 477.8 | 1300 | 1300 | 1300 | 67900 | 610000 | Ivoire clair | Ivoire clair | 611275 | 292922 | 9 | 477.795 | 1279.37 | 67919.5 | 32546.9 | ...de stratigraphies = default; ...de matériaux et couleurs = Ivoire clair; ...de matériaux et couleurs - 1 = Ivoire clair; ...de matériaux et couleurs - 2 = Ivoire clair
Enveloppe 664708 | Rez-de-chaussée | Enveloppe | 664708 | 366 | 9000 | 1977773087 | 1977773087 | 0 | 0 | 0996 | 03 | Rez-de-chaussée | no | rectangle | 36.6915 | 477.795 | 0.0128504 | 90.3416 | 477.795 | 270.342 | HAUT Rez-de-chaussée (Niveau 1 2343) | 0.0128504 | <aucun> | Rez-de-chaussée (Rez-de-chaussée 1047) | <aucun> | 36.7 | 36.7 | 477.8 | 477.8 | 300 | 300 | 300 | 17500 | 160000 | Ivoire clair | Ivoire clair | 157779 | 157779 | 9 | 477.795 | 330.224 | 17531 | 17531 | ...de stratigraphies = default; ...de matériaux et couleurs = Ivoire clair; ...de matériaux et couleurs - 1 = Ivoire clair; ...de matériaux et couleurs - 2 = Ivoire clair
Enveloppe 603926 | Rez-de-chaussée | Enveloppe | 603926 | 366 | 9000 | 1977773087 | 1977773087 | 0 | 0 | 0981 | 03 | Rez-de-chaussée | yes | rectangle | 112.479 | 653.91 | 200 | 90.2887 | 653.91 | 270.289 | HAUT Niveau 1 (Niveau 2 13545) | 9.23706e-12 | <aucun> | Rez-de-chaussée (Rez-de-chaussée 1047) | <aucun> | 112.5 | 112.5 | 653.9 | 653.9 | 1000 | 1000 | 1000 | 73600 | 660000 | Ivoire clair | Ivoire clair | 661959 | 238557 | 9 | 653.91 | 1012.31 | 73551 | 26506.3 | ...de stratigraphies = default; ...de matériaux et couleurs = Ivoire clair; ...de matériaux et couleurs - 1 = Ivoire clair; ...de matériaux et couleurs - 2 = Ivoire clair
Enveloppe 663288 | Rez-de-chaussée | Enveloppe | 663288 | 366 | 9000 | 1977773087 | 1977773087 | 0 | 0 | 0985 | 03 | Rez-de-chaussée | no | rectangle | 26.0487 | 477.795 | 0.0128504 | 130.176 | 477.795 | 310.176 | HAUT Rez-de-chaussée (Niveau 1 2343) | 0.0128504 | <aucun> | Rez-de-chaussée (Rez-de-chaussée 1047) | <aucun> | 26 | 26 | 477.8 | 477.8 | 200 | 200 | 200 | 12400 | 110000 | Ivoire clair | Ivoire clair | 112014 | 112014 | 9 | 477.795 | 234.439 | 12446 | 12446 | ...de stratigraphies = default; ...de matériaux et couleurs = Ivoire clair; ...de matériaux et couleurs - 1 = Ivoire clair; ...de matériaux et couleurs - 2 = Ivoire clair
Enveloppe 663740 | Rez-de-chaussée | Enveloppe | 663740 | 366 | 9000 | 1977773087 | 1977773087 | 1 | 0 | 0988 | 03 | Rez-de-chaussée | no | rectangle | 36.5629 | 477.795 | 0.0128504 | 135.721 | 477.795 | 315.721 | HAUT Rez-de-chaussée (Niveau 1 2343) | 0.0128504 | <aucun> | Rez-de-chaussée (Rez-de-chaussée 1047) | <aucun> | 36.6 | 36.6 | 477.8 | 477.8 | 300 | 300 | 300 | 17500 | 160000 | Ivoire clair | Ivoire clair | 157226 | 157226 | 9 | 477.795 | 329.066 | 17469.6 | 17469.6 | ...de stratigraphies = default; ...de matériaux et couleurs = Ivoire clair; ...de matériaux et couleurs - 1 = Ivoire clair; ...de matériaux et couleurs - 2 = Ivoire clair
Enveloppe 663793 | Rez-de-chaussée | Enveloppe | 663793 | 366 | 9000 | 1977773087 | 1977773087 | 0 | 0 | 0989 | 03 | Rez-de-chaussée | no | rectangle | 31.2911 | 477.795 | 0.0128504 | 37.8988 | 477.795 | 217.899 | HAUT Rez-de-chaussée (Niveau 1 2343) | 0.0128504 | <aucun> | Rez-de-chaussée (Rez-de-chaussée 1047) | <aucun> | 31.3 | 31.3 | 477.8 | 477.8 | 300 | 300 | 300 | 15000 | 140000 | Ivoire clair | Ivoire clair | 134557 | 134557 | 9 | 477.795 | 281.62 | 14950.8 | 14950.8 | ...de stratigraphies = default; ...de matériaux et couleurs = Ivoire clair; ...de matériaux et couleurs - 1 = Ivoire clair; ...de matériaux et couleurs - 2 = Ivoire clair
Enveloppe 663362 | Rez-de-chaussée | Enveloppe | 663362 | 366 | 9000 | 1977773087 | 1977773087 | 0 | 0 | 0986 | 03 | Rez-de-chaussée | no | rectangle | 31.8106 | 477.795 | 0.0128504 | 43.1635 | 477.795 | 223.164 | HAUT Rez-de-chaussée (Niveau 1 2343) | 0.0128504 | <aucun> | Rez-de-chaussée (Rez-de-chaussée 1047) | <aucun> | 31.8 | 31.8 | 477.8 | 477.8 | 300 | 300 | 300 | 15200 | 140000 | Ivoire clair | Ivoire clair | 136790 | 136790 | 9 | 477.795 | 286.295 | 15198.9 | 15198.9 | ...de stratigraphies = default; ...de matériaux et couleurs = Ivoire clair; ...de matériaux et couleurs - 1 = Ivoire clair; ...de matériaux et couleurs - 2 = Ivoire clair
Enveloppe 663416 | Rez-de-chaussée | Enveloppe | 663416 | 366 | 9000 | 1977773087 | 1977773087 | 1 | 0 | 0987 | 03 | Rez-de-chaussée | no | rectangle | 26.6608 | 477.795 | 0.0128504 | 141.387 | 477.795 | 321.387 | HAUT Rez-de-chaussée (Niveau 1 2343) | 0.0128504 | <aucun> | Rez-de-chaussée (Rez-de-chaussée 1047) | <aucun> | 26.7 | 26.7 | 477.8 | 477.8 | 200 | 200 | 200 | 12800 | 120000 | Ivoire clair | Ivoire clair | 114646 | 114646 | 9 | 477.795 | 239.947 | 12738.4 | 12738.4 | ...de stratigraphies = default; ...de matériaux et couleurs = Ivoire clair; ...de matériaux et couleurs - 1 = Ivoire clair; ...de matériaux et couleurs - 2 = Ivoire clair
Enveloppe 11562 | Rez-de-chaussée | Enveloppe | 11562 | 366 | 9000 | 1977773087 | 1977773087 | 0 | 0 | 0052 | 03 | Rez-de-chaussée | no | rectangle | 84.8884 | 477.795 | 0.0128504 | 90.8599 | 477.795 | 270.86 | HAUT Rez-de-chaussée (Niveau 1 2343) | 0.0128504 | <aucun> | Rez-de-chaussée (Rez-de-chaussée 1047) | <aucun> | 84.9 | 84.9 | 477.8 | 477.8 | 800 | 800 | 800 | 40600 | 370000 | Ivoire clair | Ivoire clair | 365034 | 365034 | 9 | 477.795 | 763.996 | 40559.3 | 40559.3 | ...de stratigraphies = default; ...de matériaux et couleurs = Ivoire clair; ...de matériaux et couleurs - 1 = Ivoire clair; ...de matériaux et couleurs - 2 = Ivoire clair
Enveloppe 7243 | Rez-de-chaussée | Enveloppe | 7243 | 366 | 9000 | 1977773087 | 1977773087 | 0 | 0 | 0040 | 03 | Rez-de-chaussée | no | rectangle | 28.8151 | 477.795 | 0.0128504 | 49.3539 | 477.795 | 229.354 | HAUT Rez-de-chaussée (Niveau 1 2343) | 0.0128504 | <aucun> | Rez-de-chaussée (Rez-de-chaussée 1047) | <aucun> | 28.8 | 28.8 | 477.8 | 477.8 | 300 | 300 | 300 | 13800 | 120000 | Ivoire clair | Ivoire clair | 123909 | 123909 | 9 | 477.795 | 259.336 | 13767.7 | 13767.7 | ...de stratigraphies = default; ...de matériaux et couleurs = Ivoire clair; ...de matériaux et couleurs - 1 = Ivoire clair; ...de matériaux et couleurs - 2 = Ivoire clair
Enveloppe 7305 | Rez-de-chaussée | Enveloppe | 7305 | 366 | 9000 | 1977773087 | 1977773087 | 1 | 0 | 0041 | 03 | Rez-de-chaussée | no | rectangle | 196.976 | 477.795 | 0.0128504 | 90.2083 | 477.795 | 270.208 | HAUT Rez-de-chaussée (Niveau 1 2343) | 0.0128504 | <aucun> | Rez-de-chaussée (Rez-de-chaussée 1047) | <aucun> | 197 | 197 | 477.8 | 477.8 | 1800 | 1800 | 1800 | 94100 | 850000 | Ivoire clair | Ivoire clair | 847030 | 847030 | 9 | 477.795 | 1772.79 | 94114.5 | 94114.5 | ...de stratigraphies = default; ...de matériaux et couleurs = Ivoire clair; ...de matériaux et couleurs - 1 = Ivoire clair; ...de matériaux et couleurs - 2 = Ivoire clair
Enveloppe 7213 | Rez-de-chaussée | Enveloppe | 7213 | 366 | 9000 | 1977773087 | 1977773087 | 1 | 0 | 0038 | 03 | Rez-de-chaussée | no | rectangle | 198.348 | 477.795 | 0.0128504 | 179.894 | 477.795 | 359.894 | HAUT Rez-de-chaussée (Niveau 1 2343) | 0.0128504 | <aucun> | Rez-de-chaussée (Rez-de-chaussée 1047) | <aucun> | 198.3 | 198.3 | 477.8 | 477.8 | 1800 | 1800 | 1800 | 94700 | 850000 | Ivoire clair | Ivoire clair | 852926 | 852926 | 9 | 477.795 | 1785.13 | 94769.5 | 94769.5 | ...de stratigraphies = default; ...de matériaux et couleurs = Ivoire clair; ...de matériaux et couleurs - 1 = Ivoire clair; ...de matériaux et couleurs - 2 = Ivoire clair
Enveloppe 7228 | Rez-de-chaussée | Enveloppe | 7228 | 366 | 9000 | 1977773087 | 1977773087 | 1 | 0 | 0039 | 03 | Rez-de-chaussée | no | rectangle | 140.119 | 477.795 | 0.0128504 | 45.0507 | 477.795 | 225.051 | HAUT Rez-de-chaussée (Niveau 1 2343) | 0.0128504 | <aucun> | Rez-de-chaussée (Rez-de-chaussée 1047) | <aucun> | 140.1 | 140.1 | 477.8 | 477.8 | 1300 | 1300 | 1300 | 66900 | 600000 | Ivoire clair | Ivoire clair | 602532 | 183228 | 9 | 477.795 | 1261.07 | 66948 | 20358.7 | ...de stratigraphies = default; ...de matériaux et couleurs = Ivoire clair; ...de matériaux et couleurs - 1 = Ivoire clair; ...de matériaux et couleurs - 2 = Ivoire clair
Enveloppe 7320 | Rez-de-chaussée | Enveloppe | 7320 | 366 | 9000 | 1977773087 | 1977773087 | 1 | 0 | 0042 | 03 | Rez-de-chaussée | no | rectangle | 98.6093 | 477.795 | 0.0128504 | 46.5877 | 477.795 | 226.588 | HAUT Rez-de-chaussée (Niveau 1 2343) | 0.0128504 | <aucun> | Rez-de-chaussée (Rez-de-chaussée 1047) | <aucun> | 98.6 | 98.6 | 477.8 | 477.8 | 900 | 900 | 900 | 47100 | 420000 | Ivoire clair | Ivoire clair | 424036 | 424036 | 9 | 477.795 | 887.484 | 47115.1 | 47115.1 | ...de stratigraphies = default; ...de matériaux et couleurs = Ivoire clair; ...de matériaux et couleurs - 1 = Ivoire clair; ...de matériaux et couleurs - 2 = Ivoire clair
Enveloppe 7452 | Rez-de-chaussée | Enveloppe | 7452 | 366 | 9000 | 1977773087 | 1977773087 | 0 | 0 | 0045 | 03 | Rez-de-chaussée | no | rectangle | 193.603 | 397.095 | 0.0128504 | 179.831 | 397.095 | 359.831 | HAUT Rez-de-chaussée (Niveau 1 2343) | -80.6871 | <aucun> | Rez-de-chaussée (Rez-de-chaussée 1047) | <aucun> | 193.6 | 193.6 | 397.1 | 397.1 | 1700 | 1700 | 1700 | 76900 | 690000 | Ivoire clair | Ivoire clair | 691910 | 691910 | 9 | 397.095 | 1742.43 | 76878.8 | 76878.8 | ...de stratigraphies = default; ...de matériaux et couleurs = Ivoire clair; ...de matériaux et couleurs - 1 = Ivoire clair; ...de matériaux et couleurs - 2 = Ivoire clair
Enveloppe 7350 | Rez-de-chaussée | Enveloppe | 7350 | 366 | 9000 | 1977773087 | 1977773087 | 1 | 0 | 0043 | 03 | Rez-de-chaussée | no | rectangle | 102.495 | 477.795 | 0.0128504 | 45 | 477.795 | 225 | HAUT Rez-de-chaussée (Niveau 1 2343) | 0.0128504 | <aucun> | Rez-de-chaussée (Rez-de-chaussée 1047) | <aucun> | 102.5 | 102.5 | 477.8 | 477.8 | 900 | 900 | 900 | 49000 | 440000 | Ivoire clair | Ivoire clair | 440745 | 440745 | 9 | 477.795 | 922.456 | 48971.7 | 48971.7 | ...de stratigraphies = default; ...de matériaux et couleurs = Ivoire clair; ...de matériaux et couleurs - 1 = Ivoire clair; ...de matériaux et couleurs - 2 = Ivoire clair
Enveloppe 2545 | Rez-de-chaussée | Enveloppe | 2545 | 366 | 9000 | 1977773087 | 1977773087 | 0 | 0 | 0006 | 03 | Rez-de-chaussée | yes | rectangle | 127.611 | 397.695 | 0.0128504 | 90.4996 | 397.695 | 270.5 | HAUT Rez-de-chaussée (Niveau 1 2343) | -80.0871 | <aucun> | Rez-de-chaussée (Rez-de-chaussée 1047) | <aucun> | 127.6 | 127.6 | 397.7 | 397.7 | 1200 | 1200 | 1200 | 50700 | 460000 | Ivoire clair | Ivoire clair | 470975 | 470975 | 9.28021 | 397.695 | 1184.26 | 50750.5 | 50750.5 | ...de stratigraphies = default; ...de matériaux et couleurs = Ivoire clair; ...de matériaux et couleurs - 1 = Ivoire clair; ...de matériaux et couleurs - 2 = Ivoire clair
Enveloppe 2590 | Rez-de-chaussée | Enveloppe | 2590 | 366 | 9000 | 1977773087 | 1977773087 | 1 | 0 | 0007 | 03 | Rez-de-chaussée | no | rectangle | 36.1778 | 399.097 | 0.0128504 | 87.162 | 399.097 | 267.162 | HAUT Rez-de-chaussée (Niveau 1 2343) | -78.6853 | <aucun> | Rez-de-chaussée (Rez-de-chaussée 1047) | <aucun> | 36.2 | 36.2 | 399.1 | 399.1 | 300 | 300 | 300 | 14400 | 130000 | Ivoire clair | Ivoire clair | 129946 | 129946 | 9 | 399.097 | 325.6 | 14438.5 | 14438.5 | ...de stratigraphies = default; ...de matériaux et couleurs = Ivoire clair; ...de matériaux et couleurs - 1 = Ivoire clair; ...de matériaux et couleurs - 2 = Ivoire clair
Enveloppe 3133 | Rez-de-chaussée | Enveloppe | 3133 | 366 | 9000 | 1977773087 | 1977773087 | 0 | 0 | 0022 | 03 | Rez-de-chaussée | no | rectangle | 96.3451 | 477.795 | 0.0128504 | 89.6756 | 477.795 | 269.676 | HAUT Rez-de-chaussée (Niveau 1 2343) | 0.0128504 | <aucun> | Rez-de-chaussée (Rez-de-chaussée 1047) | <aucun> | 96.3 | 96.3 | 477.8 | 477.8 | 900 | 900 | 900 | 46000 | 410000 | Ivoire clair | Ivoire clair | 414299 | 268499 | 9 | 477.795 | 867.106 | 46033.3 | 29833.3 | ...de stratigraphies = default; ...de matériaux et couleurs = Ivoire clair; ...de matériaux et couleurs - 1 = Ivoire clair; ...de matériaux et couleurs - 2 = Ivoire clair
Enveloppe 365779 | Rez-de-chaussée | Enveloppe | 365779 | 366 | 9000 | 1977773087 | 1977773087 | 1 | 1 | 0585 | 03 | Rez-de-chaussée | no | rectangle | 170.703 | 449.795 | -2 | 90.0118 | 449.795 | 270.012 | HAUT Rez-de-chaussée (Niveau 1 2343) | -30 | <aucun> | Rez-de-chaussée (Rez-de-chaussée 1047) | <aucun> | 170.7 | 170.7 | 449.8 | 449.8 | 1500 | 1500 | 1500 | 76800 | 690000 | Ivoire clair | Ivoire clair | 691033 | 691033 | 9 | 449.795 | 1536.33 | 76781.4 | 76781.4 | ...de stratigraphies = default; ...de matériaux et couleurs = Ivoire clair; ...de matériaux et couleurs - 1 = Ivoire clair; ...de matériaux et couleurs - 2 = Ivoire clair
Enveloppe 365735 | Rez-de-chaussée | Enveloppe | 365735 | 366 | 9000 | 1977773087 | 1977773087 | 1 | 1 | 0584 | 03 | Rez-de-chaussée | no | rectangle | 107.426 | 479.808 | -2 | 0.0371683 | 479.808 | 180.037 | HAUT Rez-de-chaussée (Niveau 1 2343) | 0.0128504 | <aucun> | Rez-de-chaussée (Rez-de-chaussée 1047) | <aucun> | 107.4 | 107.4 | 479.8 | 479.8 | 1000 | 1000 | 1000 | 51500 | 460000 | Ivoire clair | Ivoire clair | 463894 | 463894 | 9 | 479.808 | 966.832 | 51543.7 | 51543.7 | ...de stratigraphies = default; ...de matériaux et couleurs = Ivoire clair; ...de matériaux et couleurs - 1 = Ivoire clair; ...de matériaux et couleurs - 2 = Ivoire clair
Enveloppe 366967 | Rez-de-chaussée | Enveloppe | 366967 | 366 | 9000 | 1977773087 | 1977773087 | 1 | 1 | 0590 | 03 | Rez-de-chaussée | no | rectangle | 281.083 | 477.795 | 0.0128504 | 89.6476 | 477.795 | 269.648 | HAUT Rez-de-chaussée (Niveau 1 2343) | 0.0128504 | <aucun> | Rez-de-chaussée (Rez-de-chaussée 1047) | <aucun> | 281.1 | 281.1 | 477.8 | 477.8 | 2500 | 2500 | 2500 | 134300 | 1210000 | Ivoire clair | Ivoire clair | 1208699 | 1208699 | 9 | 477.795 | 2529.74 | 134300 | 134300 | ...de stratigraphies = default; ...de matériaux et couleurs = Ivoire clair; ...de matériaux et couleurs - 1 = Ivoire clair; ...de matériaux et couleurs - 2 = Ivoire clair
Enveloppe 364413 | Rez-de-chaussée | Enveloppe | 364413 | 366 | 9000 | 1977773087 | 1977773087 | 0 | 1 | 0579 | 03 | Rez-de-chaussée | no | rectangle | 25.4028 | 479.808 | -2 | 88.9442 | 479.808 | 268.944 | HAUT Rez-de-chaussée (Niveau 1 2343) | 0.0128504 | <aucun> | Rez-de-chaussée (Rez-de-chaussée 1047) | <aucun> | 25.4 | 25.4 | 479.8 | 479.8 | 200 | 200 | 200 | 12200 | 110000 | Ivoire clair | Ivoire clair | 109696 | 109696 | 9 | 479.808 | 228.625 | 12188.5 | 12188.5 | ...de stratigraphies = default; ...de matériaux et couleurs = Ivoire clair; ...de matériaux et couleurs - 1 = Ivoire clair; ...de matériaux et couleurs - 2 = Ivoire clair
Enveloppe 364456 | Rez-de-chaussée | Enveloppe | 364456 | 366 | 9000 | 1977773087 | 1977773087 | 1 | 1 | 0580 | 03 | Rez-de-chaussée | no | rectangle | 104.443 | 479.808 | -2 | 0.0371683 | 479.808 | 180.037 | HAUT Rez-de-chaussée (Niveau 1 2343) | 0.0128504 | <aucun> | Rez-de-chaussée (Rez-de-chaussée 1047) | <aucun> | 104.4 | 104.4 | 479.8 | 479.8 | 900 | 900 | 900 | 50100 | 450000 | Ivoire clair | Ivoire clair | 451014 | 451014 | 9 | 479.808 | 939.988 | 50112.7 | 50112.7 | ...de stratigraphies = default; ...de matériaux et couleurs = Ivoire clair; ...de matériaux et couleurs - 1 = Ivoire clair; ...de matériaux et couleurs - 2 = Ivoire clair
Enveloppe 3181 | Rez-de-chaussée | Enveloppe | 3181 | 366 | 9000 | 1977773087 | 1977773087 | 0 | 0 | 0023 | 03 | Rez-de-chaussée | yes | rectangle | 454.438 | 477.795 | 0.0128504 | 90.4339 | 477.795 | 270.434 | HAUT Rez-de-chaussée (Niveau 1 2343) | 0.0128504 | <aucun> | Rez-de-chaussée (Rez-de-chaussée 1047) | <aucun> | 454.5 | 454.5 | 477.8 | 477.8 | 4500 | 4500 | 4500 | 217200 | 2390000 | Ivoire clair | Ivoire clair | 2184959 | 1970830 | 10.063 | 477.795 | 4573 | 217129 | 197023 | ...de stratigraphies = default; ...de matériaux et couleurs = Ivoire clair; ...de matériaux et couleurs - 1 = Ivoire clair; ...de matériaux et couleurs - 2 = Ivoire clair
Enveloppe 10338 | Rez-de-chaussée | Enveloppe | 10338 | 366 | 9000 | 1977773087 | 1977773087 | 0 | 0 | 0048 | 03 | Rez-de-chaussée | no | rectangle | 309.579 | 477.795 | 0.0128504 | 90.1355 | 477.795 | 270.136 | HAUT Rez-de-chaussée (Niveau 1 2343) | 0.0128504 | <aucun> | Rez-de-chaussée (Rez-de-chaussée 1047) | <aucun> | 309.5 | 309.5 | 477.8 | 477.8 | 2800 | 2800 | 2800 | 147900 | 1330000 | Ivoire clair | Ivoire clair | 1331239 | 1331239 | 9 | 477.795 | 2786.21 | 147915 | 147915 | ...de stratigraphies = default; ...de matériaux et couleurs = Ivoire clair; ...de matériaux et couleurs - 1 = Ivoire clair; ...de matériaux et couleurs - 2 = Ivoire clair
Enveloppe courbe 672578 | Rez-de-chaussée | Enveloppe courbe | 672578 | 367 | 9001 | -746779066 | -746779066 | 1 | 0 | 50 | 03 | Rez-de-chaussée | no | rectangle | 25.5668 | 477.795 | 0.0128504 | 22.6199 | 477.795 | 202.62 | HAUT Rez-de-chaussée (Niveau 1 2343) | 0.0128504 | <aucun> | Rez-de-chaussée (Rez-de-chaussée 1047) | <aucun> | 25.6 | 25.6 | 477.8 | 477.8 | 100 | 200 | 200 | 12200 | 110000 | Blanc | Blanc | 108615 | 108615 | 8.89144 | 477.795 | 227.326 | 12215.7 | 12215.7 | ...de matériaux et couleurs = Blanc; ...de matériaux et couleurs - 1 = Blanc; ...de matériaux et couleurs - 2 = Blanc; ...de stratigraphies = default | IFC_Pset_Géométrie - Rayon: 64.7604 cm; Point arc: [535,4; 716,2] cm; Centre: [466,4; 721,9] cm; Angle de la Tangente: 13.8865 deg
Enveloppe courbe 672288 | Rez-de-chaussée | Enveloppe courbe | 672288 | 367 | 9001 | -746779066 | -746779066 | 0 | 0 | 49 | 03 | Rez-de-chaussée | no | rectangle | 25.2954 | 477.795 | 0.0128504 | 27.0534 | 477.795 | 207.053 | HAUT Rez-de-chaussée (Niveau 1 2343) | 0.0128504 | <aucun> | Rez-de-chaussée (Rez-de-chaussée 1047) | <aucun> | 25.3 | 25.3 | 477.8 | 477.8 | 100 | 200 | 200 | 12100 | 110000 | Blanc | Blanc | 107051 | 107051 | 8.85745 | 477.795 | 224.053 | 12086 | 12086 | ...de matériaux et couleurs = Blanc; ...de matériaux et couleurs - 1 = Blanc; ...de matériaux et couleurs - 2 = Blanc; ...de stratigraphies = default | IFC_Pset_Géométrie - Rayon: 53.5726 cm; Point arc: [675,2; 716,6] cm; Centre: [733,0; 721,8] cm; Angle de la Tangente: 16.1033 deg
Enveloppe courbe 671853 | Rez-de-chaussée | Enveloppe courbe | 671853 | 367 | 9001 | -746779066 | -746779066 | 0 | 0 | 48 | 03 | Rez-de-chaussée | no | rectangle | 25.3517 | 477.795 | 0.0128504 | 28.6815 | 477.795 | 208.682 | HAUT Rez-de-chaussée (Niveau 1 2343) | 0.0128504 | <aucun> | Rez-de-chaussée (Rez-de-chaussée 1047) | <aucun> | 25.3 | 25.3 | 477.8 | 477.8 | 100 | 200 | 200 | 12100 | 110000 | Blanc | Blanc | 107734 | 107734 | 8.89413 | 477.795 | 225.481 | 12112.9 | 12112.9 | ...de matériaux et couleurs = Blanc; ...de matériaux et couleurs - 1 = Blanc; ...de matériaux et couleurs - 2 = Blanc; ...de stratigraphies = default | IFC_Pset_Géométrie - Rayon: 50.6439 cm; Point arc: [846,3; 718,1] cm; Centre: [901,1; 724,5] cm; Angle de la Tangente: 16.9173 deg
Enveloppe 442677 | Niveau 1 | Enveloppe | 442677 | 366 | 9000 | 1908701706 | 1977773087 | 0 | 1 | 0743 | 04 | Niveau 1 | no | rectangle | 62.1909 | 376.102 | 0.0128504 | 179.521 | 376.102 | 359.521 | HAUT Niveau 1 (Niveau 2 13545) | 6.03961e-12 | <aucun> | Niveau 1 (Niveau 1 2343) | <aucun> | 62.2 | 62.2 | 376.1 | 376.1 | 600 | 600 | 600 | 23400 | 210000 | Gris lumière | Ivoire clair | 210511 | 210511 | 9 | 376.102 | 559.718 | 23390.1 | 23390.1 | ...de stratigraphies = default; ...de matériaux et couleurs - 1 = Ivoire clair; ...de matériaux et couleurs - 2 = Ivoire clair; ...de matériaux et couleurs = Gris lumière
Enveloppe 442674 | Niveau 1 | Enveloppe | 442674 | 366 | 9000 | 1908701706 | 1977773087 | 0 | 1 | 0742 | 04 | Niveau 1 | no | rectangle | 88.2269 | 376.102 | 0.0128504 | 179.343 | 376.102 | 359.343 | HAUT Niveau 1 (Niveau 2 13545) | 6.03961e-12 | <aucun> | Niveau 1 (Niveau 1 2343) | <aucun> | 88.2 | 88.2 | 376.1 | 376.1 | 800 | 800 | 800 | 33200 | 300000 | Gris lumière | Ivoire clair | 298641 | 298641 | 9 | 376.102 | 794.042 | 33182.3 | 33182.3 | ...de stratigraphies = default; ...de matériaux et couleurs - 1 = Ivoire clair; ...de matériaux et couleurs - 2 = Ivoire clair; ...de matériaux et couleurs = Gris lumière
Enveloppe 533221 | Niveau 1 | Enveloppe | 533221 | 366 | 9000 | 1908701706 | 1977773087 | 1 | 1 | 0858 | 04 | Niveau 1 | no | rectangle | 97.0207 | 376.102 | 0.0128504 | 89.6761 | 376.102 | 269.676 | HAUT Niveau 1 (Niveau 2 13545) | 4.9738e-12 | <aucun> | Niveau 1 (Niveau 1 2343) | <aucun> | 97 | 97 | 376.1 | 376.1 | 900 | 900 | 900 | 36500 | 330000 | Gris lumière | Ivoire clair | 328407 | 328407 | 9 | 376.102 | 873.186 | 36489.7 | 36489.7 | ...de stratigraphies = default; ...de matériaux et couleurs - 1 = Ivoire clair; ...de matériaux et couleurs - 2 = Ivoire clair; ...de matériaux et couleurs = Gris lumière
Enveloppe 425221 | Niveau 1 | Enveloppe | 425221 | 366 | 9000 | 1908701706 | 1977773087 | 1 | 1 | 0706 | 04 | Niveau 1 | no | rectangle | 34.6432 | 376.102 | 0.0128504 | 178.875 | 376.102 | 358.875 | HAUT Niveau 1 (Niveau 2 13545) | 6.75016e-12 | <aucun> | Niveau 1 (Niveau 1 2343) | <aucun> | 34.6 | 34.6 | 376.1 | 376.1 | 300 | 300 | 300 | 13000 | 120000 | Gris lumière | Ivoire clair | 117265 | 117265 | 9 | 376.102 | 311.789 | 13029.4 | 13029.4 | ...de stratigraphies = default; ...de matériaux et couleurs - 1 = Ivoire clair; ...de matériaux et couleurs - 2 = Ivoire clair; ...de matériaux et couleurs = Gris lumière
Enveloppe 425244 | Niveau 1 | Enveloppe | 425244 | 366 | 9000 | 1908701706 | 1977773087 | 0 | 1 | 0707 | 04 | Niveau 1 | no | rectangle | 48.7989 | 376.102 | 0.0128504 | 0.905984 | 376.102 | 180.906 | HAUT Niveau 1 (Niveau 2 13545) | 6.75016e-12 | <aucun> | Niveau 1 (Niveau 1 2343) | <aucun> | 48.8 | 48.8 | 376.1 | 376.1 | 400 | 400 | 400 | 18400 | 170000 | Gris lumière | Ivoire clair | 165180 | 165180 | 9 | 376.102 | 439.19 | 18353.4 | 18353.4 | ...de stratigraphies = default; ...de matériaux et couleurs - 1 = Ivoire clair; ...de matériaux et couleurs - 2 = Ivoire clair; ...de matériaux et couleurs = Gris lumière
Enveloppe 425135 | Niveau 1 | Enveloppe | 425135 | 366 | 9000 | 1908701706 | 1977773087 | 1 | 1 | 0704 | 04 | Niveau 1 | no | rectangle | 69.8495 | 376.102 | 0.0128504 | 178.652 | 376.102 | 358.652 | HAUT Niveau 1 (Niveau 2 13545) | 6.75016e-12 | <aucun> | Niveau 1 (Niveau 1 2343) | <aucun> | 69.8 | 69.8 | 376.1 | 376.1 | 600 | 600 | 600 | 26300 | 240000 | Gris lumière | Ivoire clair | 236435 | 236435 | 9 | 376.102 | 628.646 | 26270.6 | 26270.6 | ...de stratigraphies = default; ...de matériaux et couleurs - 1 = Ivoire clair; ...de matériaux et couleurs - 2 = Ivoire clair; ...de matériaux et couleurs = Gris lumière
Enveloppe 425157 | Niveau 1 | Enveloppe | 425157 | 366 | 9000 | 1908701706 | 1977773087 | 0 | 1 | 0705 | 04 | Niveau 1 | no | rectangle | 67.4784 | 376.102 | 0.0128504 | 0.170109 | 376.102 | 180.17 | HAUT Niveau 1 (Niveau 2 13545) | 6.75016e-12 | <aucun> | Niveau 1 (Niveau 1 2343) | <aucun> | 67.5 | 67.5 | 376.1 | 376.1 | 600 | 600 | 600 | 25400 | 230000 | Gris lumière | Ivoire clair | 228409 | 228409 | 9 | 376.102 | 607.306 | 25378.8 | 25378.8 | ...de stratigraphies = default; ...de matériaux et couleurs - 1 = Ivoire clair; ...de matériaux et couleurs - 2 = Ivoire clair; ...de matériaux et couleurs = Gris lumière
Enveloppe 425391 | Niveau 1 | Enveloppe | 425391 | 366 | 9000 | 1908701706 | 1977773087 | 1 | 1 | 0708 | 04 | Niveau 1 | no | rectangle | 55.5867 | 376.102 | 0.0128504 | 179.425 | 376.102 | 359.425 | HAUT Niveau 1 (Niveau 2 13545) | 6.75016e-12 | <aucun> | Niveau 1 (Niveau 1 2343) | <aucun> | 55.6 | 55.6 | 376.1 | 376.1 | 500 | 500 | 500 | 20900 | 190000 | Gris lumière | Ivoire clair | 188157 | 188157 | 9 | 376.102 | 500.28 | 20906.3 | 20906.3 | ...de stratigraphies = default; ...de matériaux et couleurs - 1 = Ivoire clair; ...de matériaux et couleurs - 2 = Ivoire clair; ...de matériaux et couleurs = Gris lumière
Enveloppe 425414 | Niveau 1 | Enveloppe | 425414 | 366 | 9000 | 1908701706 | 1977773087 | 1 | 1 | 0709 | 04 | Niveau 1 | no | rectangle | 72.1351 | 376.102 | 0.0128504 | 179.365 | 376.102 | 359.365 | HAUT Niveau 1 (Niveau 2 13545) | 6.75016e-12 | <aucun> | Niveau 1 (Niveau 1 2343) | <aucun> | 72.1 | 72.1 | 376.1 | 376.1 | 600 | 600 | 600 | 27100 | 240000 | Gris lumière | Ivoire clair | 244172 | 244172 | 9 | 376.102 | 649.216 | 27130.2 | 27130.2 | ...de stratigraphies = default; ...de matériaux et couleurs - 1 = Ivoire clair; ...de matériaux et couleurs - 2 = Ivoire clair; ...de matériaux et couleurs = Gris lumière
Enveloppe 425477 | Niveau 1 | Enveloppe | 425477 | 366 | 9000 | 1908701706 | 1977773087 | 1 | 1 | 0710 | 04 | Niveau 1 | no | rectangle | 101.89 | 376.102 | 0.0128504 | 89.1372 | 376.102 | 269.137 | HAUT Niveau 1 (Niveau 2 13545) | 6.75016e-12 | <aucun> | Niveau 1 (Niveau 1 2343) | <aucun> | 101.9 | 101.9 | 376.1 | 376.1 | 900 | 900 | 900 | 38300 | 340000 | Gris lumière | Ivoire clair | 344891 | 344891 | 9 | 376.102 | 917.014 | 38321.2 | 38321.2 | ...de stratigraphies = default; ...de matériaux et couleurs - 1 = Ivoire clair; ...de matériaux et couleurs - 2 = Ivoire clair; ...de matériaux et couleurs = Gris lumière
Enveloppe 425112 | Niveau 1 | Enveloppe | 425112 | 366 | 9000 | 1908701706 | 1977773087 | 0 | 1 | 0703 | 04 | Niveau 1 | no | rectangle | 35.7945 | 376.102 | 0.0128504 | 88.3671 | 376.102 | 268.367 | HAUT Niveau 1 (Niveau 2 13545) | 6.75016e-12 | <aucun> | Niveau 1 (Niveau 1 2343) | <aucun> | 35.8 | 35.8 | 376.1 | 376.1 | 300 | 300 | 300 | 13500 | 120000 | Gris lumière | Ivoire clair | 121162 | 121162 | 9 | 376.102 | 322.151 | 13462.4 | 13462.4 | ...de stratigraphies = default; ...de matériaux et couleurs - 1 = Ivoire clair; ...de matériaux et couleurs - 2 = Ivoire clair; ...de matériaux et couleurs = Gris lumière
Enveloppe 423114 | Niveau 1 | Enveloppe | 423114 | 366 | 9000 | 1908701706 | 1977773087 | 0 | 1 | 0678 | 04 | Niveau 1 | no | rectangle | 129.7 | 376.102 | 0.0128504 | 179.897 | 376.102 | 359.897 | HAUT Niveau 1 (Niveau 2 13545) | 2.4869e-12 | <aucun> | Niveau 1 (Niveau 1 2343) | <aucun> | 129.7 | 129.7 | 376.1 | 376.1 | 1200 | 1200 | 1200 | 48800 | 440000 | Gris lumière | Ivoire clair | 439025 | 439025 | 9 | 376.102 | 1167.3 | 48780.5 | 48780.5 | ...de stratigraphies = default; ...de matériaux et couleurs - 1 = Ivoire clair; ...de matériaux et couleurs - 2 = Ivoire clair; ...de matériaux et couleurs = Gris lumière
Enveloppe 423177 | Niveau 1 | Enveloppe | 423177 | 366 | 9000 | 1908701706 | 1977773087 | 0 | 1 | 0679 | 04 | Niveau 1 | no | rectangle | 32.2195 | 374.102 | 0.0128504 | 92.037 | 374.102 | 272.037 | HAUT Niveau 1 (Niveau 2 13545) | -2 | <aucun> | Niveau 1 (Niveau 1 2343) | <aucun> | 32.2 | 32.2 | 374.1 | 374.1 | 300 | 300 | 300 | 12000 | 110000 | Gris lumière | Ivoire clair | 108481 | 108481 | 9 | 374.102 | 289.976 | 12053.4 | 12053.4 | ...de stratigraphies = default; ...de matériaux et couleurs - 1 = Ivoire clair; ...de matériaux et couleurs - 2 = Ivoire clair; ...de matériaux et couleurs = Gris lumière
Enveloppe 422609 | Niveau 1 | Enveloppe | 422609 | 366 | 9000 | 1908701706 | 1977773087 | 0 | 1 | 0676 | 04 | Niveau 1 | no | rectangle | 166.5 | 376.102 | 0.0128504 | 89.7205 | 376.102 | 269.72 | HAUT Niveau 1 (Niveau 2 13545) | 2.13163e-12 | <aucun> | Niveau 1 (Niveau 1 2343) | <aucun> | 166.5 | 166.5 | 376.1 | 376.1 | 1500 | 1500 | 1500 | 62600 | 560000 | Gris lumière | Ivoire clair | 563588 | 563588 | 9 | 376.102 | 1498.5 | 62620.9 | 62620.9 | ...de stratigraphies = default; ...de matériaux et couleurs - 1 = Ivoire clair; ...de matériaux et couleurs - 2 = Ivoire clair; ...de matériaux et couleurs = Gris lumière
Enveloppe 422672 | Niveau 1 | Enveloppe | 422672 | 366 | 9000 | 1908701706 | 1977773087 | 0 | 1 | 0677 | 04 | Niveau 1 | no | rectangle | 49.9645 | 376.102 | 0.0128504 | 0.41654 | 376.102 | 180.417 | HAUT Niveau 1 (Niveau 2 13545) | 2.4869e-12 | <aucun> | Niveau 1 (Niveau 1 2343) | <aucun> | 50 | 50 | 376.1 | 376.1 | 500 | 500 | 500 | 18800 | 170000 | Gris lumière | Ivoire clair | 169126 | 169126 | 9 | 376.102 | 449.68 | 18791.8 | 18791.8 | ...de stratigraphies = default; ...de matériaux et couleurs - 1 = Ivoire clair; ...de matériaux et couleurs - 2 = Ivoire clair; ...de matériaux et couleurs = Gris lumière
Enveloppe 423199 | Niveau 1 | Enveloppe | 423199 | 366 | 9000 | 1908701706 | 1977773087 | 0 | 1 | 0680 | 04 | Niveau 1 | no | rectangle | 128.689 | 374.102 | 0.0128504 | 89.8788 | 374.102 | 269.879 | HAUT Niveau 1 (Niveau 2 13545) | -2 | <aucun> | Niveau 1 (Niveau 1 2343) | <aucun> | 128.7 | 128.7 | 374.1 | 374.1 | 1200 | 1200 | 1200 | 48100 | 430000 | Gris lumière | Ivoire clair | 433286 | 433286 | 9 | 374.102 | 1158.2 | 48142.9 | 48142.9 | ...de stratigraphies = default; ...de matériaux et couleurs - 1 = Ivoire clair; ...de matériaux et couleurs - 2 = Ivoire clair; ...de matériaux et couleurs = Gris lumière
Enveloppe 423295 | Niveau 1 | Enveloppe | 423295 | 366 | 9000 | 1908701706 | 1977773087 | 0 | 1 | 0683 | 04 | Niveau 1 | no | rectangle | 20.3106 | 376.102 | 0.0128504 | 134.777 | 376.102 | 314.777 | HAUT Niveau 1 (Niveau 2 13545) | 2.4869e-12 | <aucun> | Niveau 1 (Niveau 1 2343) | <aucun> | 20.3 | 20.3 | 376.1 | 376.1 | 200 | 200 | 200 | 7600 | 70000 | Gris lumière | Ivoire clair | 68749.6 | 68749.6 | 9 | 376.102 | 182.795 | 7638.85 | 7638.85 | ...de stratigraphies = default; ...de matériaux et couleurs - 1 = Ivoire clair; ...de matériaux et couleurs - 2 = Ivoire clair; ...de matériaux et couleurs = Gris lumière
Enveloppe 423441 | Niveau 1 | Enveloppe | 423441 | 366 | 9000 | 1908701706 | 1977773087 | 0 | 1 | 0684 | 04 | Niveau 1 | no | rectangle | 190.613 | 376.102 | 0.0128504 | 179.928 | 376.102 | 359.928 | HAUT Niveau 1 (Niveau 2 13545) | 2.84217e-12 | <aucun> | Niveau 1 (Niveau 1 2343) | <aucun> | 190.6 | 190.6 | 376.1 | 376.1 | 1700 | 1700 | 1700 | 71700 | 650000 | Gris lumière | Ivoire clair | 645210 | 645210 | 9 | 376.102 | 1715.52 | 71690 | 71690 | ...de stratigraphies = default; ...de matériaux et couleurs - 1 = Ivoire clair; ...de matériaux et couleurs - 2 = Ivoire clair; ...de matériaux et couleurs = Gris lumière
Enveloppe 423262 | Niveau 1 | Enveloppe | 423262 | 366 | 9000 | 1908701706 | 1977773087 | 0 | 1 | 0681 | 04 | Niveau 1 | no | rectangle | 83.2181 | 376.102 | 0.0128504 | 44.814 | 376.102 | 224.814 | HAUT Niveau 1 (Niveau 2 13545) | 2.4869e-12 | <aucun> | Niveau 1 (Niveau 1 2343) | <aucun> | 83.2 | 83.2 | 376.1 | 376.1 | 700 | 700 | 700 | 31300 | 280000 | Gris lumière | Ivoire clair | 281687 | 281687 | 9 | 376.102 | 748.963 | 31298.5 | 31298.5 | ...de stratigraphies = default; ...de matériaux et couleurs - 1 = Ivoire clair; ...de matériaux et couleurs - 2 = Ivoire clair; ...de matériaux et couleurs = Gris lumière
Enveloppe 423292 | Niveau 1 | Enveloppe | 423292 | 366 | 9000 | 1908701706 | 1977773087 | 0 | 1 | 0682 | 04 | Niveau 1 | no | rectangle | 191.797 | 376.102 | 0.0128504 | 89.8114 | 376.102 | 269.811 | HAUT Niveau 1 (Niveau 2 13545) | 2.4869e-12 | <aucun> | Niveau 1 (Niveau 1 2343) | <aucun> | 191.8 | 191.8 | 376.1 | 376.1 | 1700 | 1700 | 1700 | 72100 | 650000 | Gris lumière | Ivoire clair | 649217 | 649217 | 9 | 376.102 | 1726.17 | 72135.2 | 72135.2 | ...de stratigraphies = default; ...de matériaux et couleurs - 1 = Ivoire clair; ...de matériaux et couleurs - 2 = Ivoire clair; ...de matériaux et couleurs = Gris lumière
Enveloppe 408091 | Niveau 1 | Enveloppe | 408091 | 366 | 9000 | 1908701706 | 1977773087 | 0 | 1 | 0670 | 04 | Niveau 1 | no | rectangle | 85.057 | 659.115 | -295 | 89.7309 | 659.115 | 269.731 | HAUT Niveau 1 (Niveau 2 13545) | -12 | <aucun> | Niveau 1 (Niveau 1 2343) | <aucun> | 85.1 | 85.1 | 659.1 | 659.1 | 800 | 800 | 800 | 56100 | 500000 | Gris lumière | Ivoire clair | 504561 | 504561 | 9 | 659.115 | 765.513 | 56062.3 | 56062.3 | ...de stratigraphies = default; ...de matériaux et couleurs - 1 = Ivoire clair; ...de matériaux et couleurs - 2 = Ivoire clair; ...de matériaux et couleurs = Gris lumière
Enveloppe 422563 | Niveau 1 | Enveloppe | 422563 | 366 | 9000 | 1908701706 | 1977773087 | 1 | 1 | 0674 | 04 | Niveau 1 | no | rectangle | 169.664 | 376.102 | 0.0128504 | 179.862 | 376.102 | 359.862 | HAUT Niveau 1 (Niveau 2 13545) | 2.13163e-12 | <aucun> | Niveau 1 (Niveau 1 2343) | <aucun> | 169.7 | 169.7 | 376.1 | 376.1 | 1500 | 1500 | 1500 | 63800 | 570000 | Gris lumière | Ivoire clair | 574300 | 574300 | 9 | 376.102 | 1526.98 | 63811.1 | 63811.1 | ...de stratigraphies = default; ...de matériaux et couleurs - 1 = Ivoire clair; ...de matériaux et couleurs - 2 = Ivoire clair; ...de matériaux et couleurs = Gris lumière
Enveloppe 422586 | Niveau 1 | Enveloppe | 422586 | 366 | 9000 | 1908701706 | 1977773087 | 0 | 1 | 0675 | 04 | Niveau 1 | no | rectangle | 169.379 | 376.102 | 0.0128504 | 89.4677 | 376.102 | 269.468 | HAUT Niveau 1 (Niveau 2 13545) | 2.13163e-12 | <aucun> | Niveau 1 (Niveau 1 2343) | <aucun> | 169.4 | 169.4 | 376.1 | 376.1 | 1500 | 1500 | 1500 | 63700 | 570000 | Gris lumière | Ivoire clair | 573336 | 573336 | 9 | 376.102 | 1524.41 | 63704 | 63704 | ...de stratigraphies = default; ...de matériaux et couleurs - 1 = Ivoire clair; ...de matériaux et couleurs - 2 = Ivoire clair; ...de matériaux et couleurs = Gris lumière
Enveloppe 414974 | Niveau 1 | Enveloppe | 414974 | 366 | 9000 | 1977773087 | 1977773087 | 1 | 0 | 0672 | 04 | Niveau 1 | no | rectangle | 175.28 | 376.102 | 0.0128504 | 179.777 | 376.102 | 359.777 | HAUT Niveau 1 (Niveau 2 13545) | 0 | <aucun> | Niveau 1 (Niveau 1 2343) | <aucun> | 175.3 | 175.3 | 376.1 | 376.1 | 1600 | 1600 | 1600 | 65900 | 590000 | Ivoire clair | Ivoire clair | 593309 | 593309 | 9 | 376.102 | 1577.52 | 65923.3 | 65923.3 | ...de stratigraphies = default; ...de matériaux et couleurs = Ivoire clair; ...de matériaux et couleurs - 1 = Ivoire clair; ...de matériaux et couleurs - 2 = Ivoire clair
Enveloppe 422540 | Niveau 1 | Enveloppe | 422540 | 366 | 9000 | 1908701706 | 1977773087 | 1 | 1 | 0673 | 04 | Niveau 1 | no | rectangle | 174.007 | 376.102 | 0.0128504 | 179.862 | 376.102 | 359.862 | HAUT Niveau 1 (Niveau 2 13545) | 2.13163e-12 | <aucun> | Niveau 1 (Niveau 1 2343) | <aucun> | 174 | 174 | 376.1 | 376.1 | 1600 | 1600 | 1600 | 65400 | 590000 | Gris lumière | Ivoire clair | 588998 | 588998 | 9 | 376.102 | 1566.06 | 65444.3 | 65444.3 | ...de stratigraphies = default; ...de matériaux et couleurs - 1 = Ivoire clair; ...de matériaux et couleurs - 2 = Ivoire clair; ...de matériaux et couleurs = Gris lumière
Enveloppe 424653 | Niveau 1 | Enveloppe | 424653 | 366 | 9000 | 1908701706 | 1977773087 | 1 | 1 | 0696 | 04 | Niveau 1 | no | rectangle | 197.549 | 376.102 | 0.0128504 | 90.0914 | 376.102 | 270.091 | HAUT Niveau 1 (Niveau 2 13545) | 6.03961e-12 | <aucun> | Niveau 1 (Niveau 1 2343) | <aucun> | 197.5 | 197.5 | 376.1 | 376.1 | 1800 | 1800 | 1800 | 74300 | 670000 | Gris lumière | Ivoire clair | 668688 | 389802 | 9 | 376.102 | 1777.94 | 74298.7 | 43311.4 | ...de stratigraphies = default; ...de matériaux et couleurs - 1 = Ivoire clair; ...de matériaux et couleurs - 2 = Ivoire clair; ...de matériaux et couleurs = Gris lumière
Enveloppe 424715 | Niveau 1 | Enveloppe | 424715 | 366 | 9000 | 1908701706 | 1977773087 | 1 | 1 | 0697 | 04 | Niveau 1 | no | rectangle | 173.285 | 376.102 | 0.0128504 | 89.71 | 376.102 | 269.71 | HAUT Niveau 1 (Niveau 2 13545) | 6.03961e-12 | <aucun> | Niveau 1 (Niveau 1 2343) | <aucun> | 173.3 | 173.3 | 376.1 | 376.1 | 1600 | 1600 | 1600 | 65200 | 590000 | Gris lumière | Ivoire clair | 586554 | 586554 | 9 | 376.102 | 1559.56 | 65172.7 | 65172.7 | ...de stratigraphies = default; ...de matériaux et couleurs - 1 = Ivoire clair; ...de matériaux et couleurs - 2 = Ivoire clair; ...de matériaux et couleurs = Gris lumière
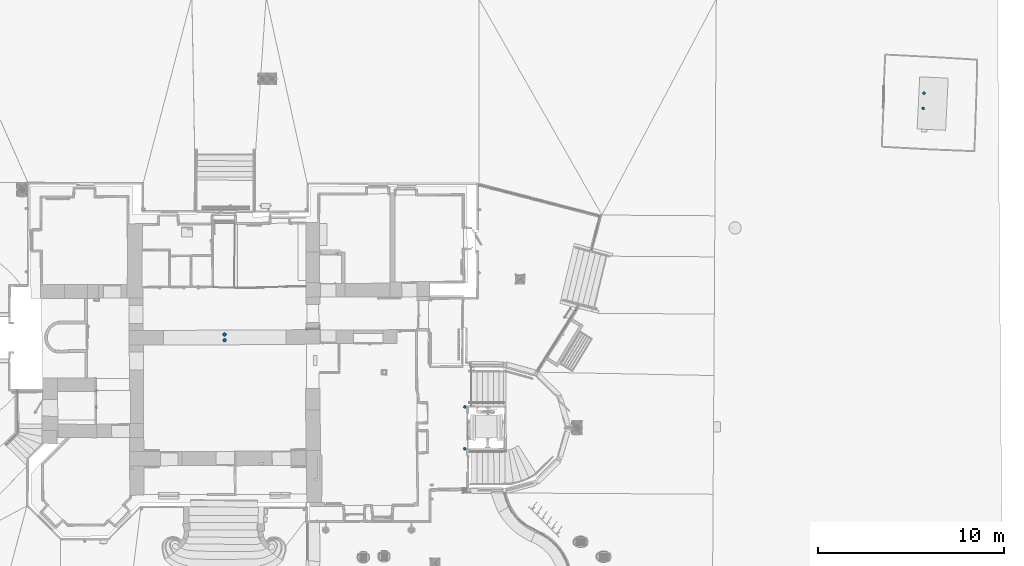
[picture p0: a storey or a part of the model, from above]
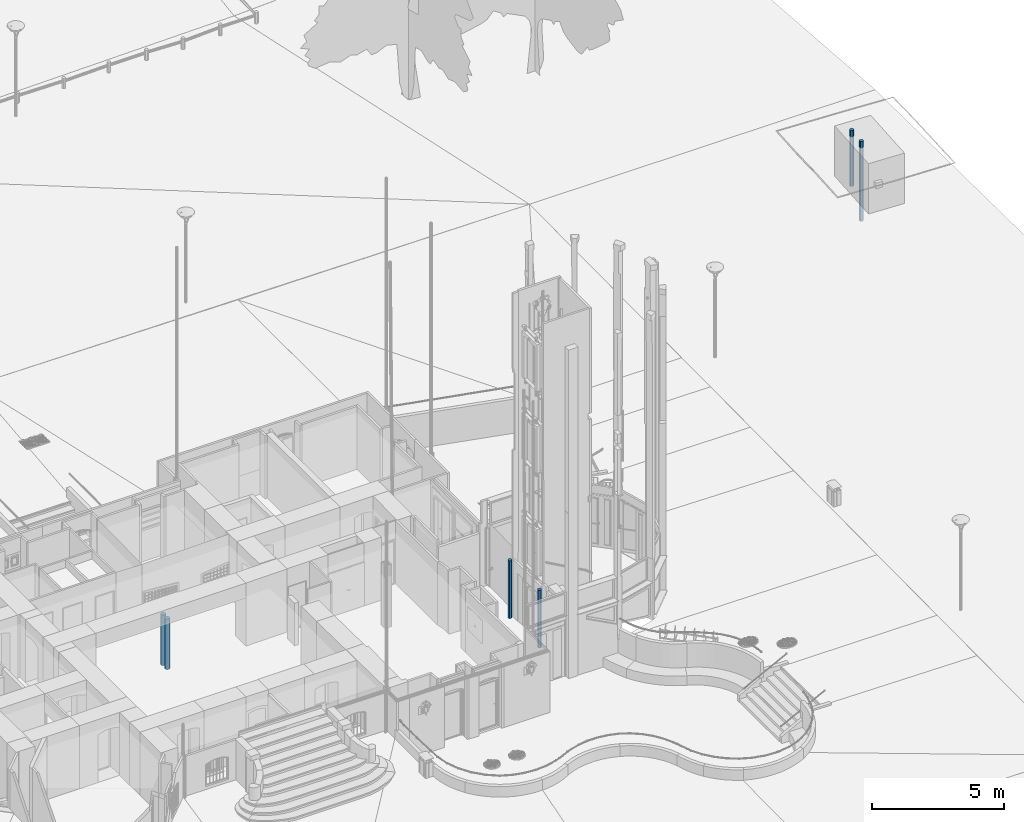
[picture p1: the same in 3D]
Properties of the parts of a building model (IFC2X3), part 32 of 37

# IfcWallStandardCase: default 90 (499)
Name | In | Description | __RECOGNIZE__, ID = IFC_Pset_Caractéristiques, ID | TPLG | TPLG_OD | 0, Crc | 1, Crc = 2, Crc | Alignment | ExternalFace | Numérotation | Numéro niveau | Titre niveau | Épaisseur VARIABLE | Forme en Élévation | Longueur (cm) = NominalLength (cm) | IFC_Pset_Géométrie, Hauteur (cm) = IFC_Pset_Géométrie_P1 (POINT initial), Hauteur (cm) | IFC_Pset_Géométrie, Cote (cm) = IFC_Pset_Géométrie_P1 (POINT initial), Cote (cm) = IFC_Pset_Géométrie_P2 (POINT final), Cote (cm) = IFC_Pset_Système de Référence Altimétrique_INFÉRIEUR, delta (cm) = IFC_Pset_Système de Référence Altimétrique_INFÉRIEUR, delta (P1) (cm) = IFC_Pset_Système de Référence Altimétrique_INFÉRIEUR, delta (P2) (cm) | IFC_Pset_Géométrie_P1 (POINT initial), Angle XY (deg) | IFC_Pset_Géométrie_P2 (POINT final), Hauteur (cm) | IFC_Pset_Géométrie_P2 (POINT final), Angle XY (deg) | IFC_Pset_Système de Référence Altimétrique_SUPÉRIEUR, NIVEAU | IFC_Pset_Système de Référence Altimétrique_SUPÉRIEUR, delta (cm) = IFC_Pset_Système de Référence Altimétrique_SUPÉRIEUR, delta (P1) (cm) = IFC_Pset_Système de Référence Altimétrique_SUPÉRIEUR, delta (P2) (cm) | IFC_Pset_Système de Référence Altimétrique_SUPÉRIEUR, sous Niveau | IFC_Pset_Système de Référence Altimétrique_INFÉRIEUR, NIVEAU | IFC_Pset_Système de Référence Altimétrique_INFÉRIEUR, sous Niveau | Longueur Pied (cm) | Longueur Tête (cm) | Hauteur Maximale (cm) | Hauteur Minimale (cm) | Surface en Plan (cm2) | Surface Pied (cm2) | Surface Tête (cm2) | Surface de la Paroi (cm2) | Volume (cm3) | Face gauche | Face droite = Face latérale | GrossVolume (cm3) | NetVolume (cm3) | NominalWidth (cm) | NominalHeight (cm) | GrossFootprintArea (cm2) = NetFootprintArea (cm2) | GrossSideArea (cm2) | NetSideArea (cm2) | Group
Enveloppe 424442 | Niveau 1 | Enveloppe | 424442 | 366 | 9000 | 1908701706 | 1977773087 | 1 | 1 | 0694 | 04 | Niveau 1 | no | rectangle | 116.872 | 376.102 | 0.0128504 | 89.9704 | 376.102 | 269.97 | HAUT Niveau 1 (Niveau 2 13545) | 5.32907e-12 | <aucun> | Niveau 1 (Niveau 1 2343) | <aucun> | 116.9 | 116.9 | 376.1 | 376.1 | 1100 | 1100 | 1100 | 44000 | 400000 | Gris lumière | Ivoire clair | 395603 | 395603 | 9 | 376.102 | 1051.85 | 43955.8 | 43955.8 | ...de stratigraphies = default; ...de matériaux et couleurs - 1 = Ivoire clair; ...de matériaux et couleurs - 2 = Ivoire clair; ...de matériaux et couleurs = Gris lumière
Enveloppe 424507 | Niveau 1 | Enveloppe | 424507 | 366 | 9000 | 1908701706 | 1977773087 | 1 | 1 | 0695 | 04 | Niveau 1 | no | rectangle | 293.557 | 376.102 | 0.0128504 | 90.0609 | 376.102 | 270.061 | HAUT Niveau 1 (Niveau 2 13545) | 5.32907e-12 | <aucun> | Niveau 1 (Niveau 1 2343) | <aucun> | 293.6 | 293.6 | 376.1 | 376.1 | 2600 | 2600 | 2600 | 110400 | 990000 | Gris lumière | Ivoire clair | 993668 | 993668 | 9 | 376.102 | 2642.02 | 110408 | 110408 | ...de stratigraphies = default; ...de matériaux et couleurs - 1 = Ivoire clair; ...de matériaux et couleurs - 2 = Ivoire clair; ...de matériaux et couleurs = Gris lumière
Enveloppe 424767 | Niveau 1 | Enveloppe | 424767 | 366 | 9000 | 1908701706 | 1977773087 | 1 | 1 | 0698 | 04 | Niveau 1 | no | rectangle | 174.456 | 376.102 | 0.0128504 | 89.9643 | 376.102 | 269.964 | HAUT Niveau 1 (Niveau 2 13545) | 6.03961e-12 | <aucun> | Niveau 1 (Niveau 1 2343) | <aucun> | 174.5 | 174.5 | 376.1 | 376.1 | 1600 | 1600 | 1600 | 65600 | 590000 | Gris lumière | Ivoire clair | 590519 | 590519 | 9 | 376.102 | 1570.1 | 65613.2 | 65613.2 | ...de stratigraphies = default; ...de matériaux et couleurs - 1 = Ivoire clair; ...de matériaux et couleurs - 2 = Ivoire clair; ...de matériaux et couleurs = Gris lumière
Enveloppe 424905 | Niveau 1 | Enveloppe | 424905 | 366 | 9000 | 1908701706 | 1977773087 | 1 | 1 | 0701 | 04 | Niveau 1 | no | rectangle | 143.549 | 376.102 | 0.0128504 | 179.504 | 376.102 | 359.504 | HAUT Niveau 1 (Niveau 2 13545) | 6.75016e-12 | <aucun> | Niveau 1 (Niveau 1 2343) | <aucun> | 143.5 | 143.5 | 376.1 | 376.1 | 1300 | 1300 | 1300 | 54000 | 490000 | Gris lumière | Ivoire clair | 485903 | 485903 | 9 | 376.102 | 1291.94 | 53989.2 | 53989.2 | ...de stratigraphies = default; ...de matériaux et couleurs - 1 = Ivoire clair; ...de matériaux et couleurs - 2 = Ivoire clair; ...de matériaux et couleurs = Gris lumière
Enveloppe 425087 | Niveau 1 | Enveloppe | 425087 | 366 | 9000 | 1908701706 | 1977773087 | 0 | 1 | 0702 | 04 | Niveau 1 | no | rectangle | 67.8309 | 376.102 | 0.0128504 | 90.4214 | 376.102 | 270.421 | HAUT Niveau 1 (Niveau 2 13545) | 6.75016e-12 | <aucun> | Niveau 1 (Niveau 1 2343) | <aucun> | 67.8 | 67.8 | 376.1 | 376.1 | 600 | 600 | 600 | 25500 | 230000 | Gris lumière | Ivoire clair | 229602 | 229602 | 9 | 376.102 | 610.478 | 25511.3 | 25511.3 | ...de stratigraphies = default; ...de matériaux et couleurs - 1 = Ivoire clair; ...de matériaux et couleurs - 2 = Ivoire clair; ...de matériaux et couleurs = Gris lumière
Enveloppe 424817 | Niveau 1 | Enveloppe | 424817 | 366 | 9000 | 1908701706 | 1977773087 | 1 | 1 | 0699 | 04 | Niveau 1 | no | rectangle | 247.222 | 376.102 | 0.0128504 | 179.638 | 376.102 | 359.638 | HAUT Niveau 1 (Niveau 2 13545) | 6.75016e-12 | <aucun> | Niveau 1 (Niveau 1 2343) | <aucun> | 247.2 | 247.2 | 376.1 | 376.1 | 2200 | 2200 | 2200 | 93000 | 840000 | Gris lumière | Ivoire clair | 836828 | 836828 | 9 | 376.102 | 2225 | 92980.8 | 92980.8 | ...de stratigraphies = default; ...de matériaux et couleurs - 1 = Ivoire clair; ...de matériaux et couleurs - 2 = Ivoire clair; ...de matériaux et couleurs = Gris lumière
Enveloppe 424841 | Niveau 1 | Enveloppe | 424841 | 366 | 9000 | 1908701706 | 1977773087 | 0 | 1 | 0700 | 04 | Niveau 1 | no | rectangle | 103.295 | 376.102 | 0.0128504 | 0.436528 | 376.102 | 180.437 | HAUT Niveau 1 (Niveau 2 13545) | 6.75016e-12 | <aucun> | Niveau 1 (Niveau 1 2343) | <aucun> | 103.3 | 103.3 | 376.1 | 376.1 | 900 | 900 | 900 | 38900 | 350000 | Gris lumière | Ivoire clair | 349646 | 349646 | 9 | 376.102 | 929.657 | 38849.6 | 38849.6 | ...de stratigraphies = default; ...de matériaux et couleurs - 1 = Ivoire clair; ...de matériaux et couleurs - 2 = Ivoire clair; ...de matériaux et couleurs = Gris lumière
Enveloppe 423940 | Niveau 1 | Enveloppe | 423940 | 366 | 9000 | 1908701706 | 1977773087 | 1 | 1 | 0687 | 04 | Niveau 1 | no | rectangle | 73.3291 | 376.102 | 0.0128504 | 0.0864368 | 376.102 | 180.086 | HAUT Niveau 1 (Niveau 2 13545) | 3.55271e-12 | <aucun> | Niveau 1 (Niveau 1 2343) | <aucun> | 73.3 | 73.3 | 376.1 | 376.1 | 700 | 700 | 700 | 27600 | 250000 | Gris lumière | Ivoire clair | 248213 | 248213 | 9 | 376.102 | 659.962 | 27579.2 | 27579.2 | ...de stratigraphies = default; ...de matériaux et couleurs - 1 = Ivoire clair; ...de matériaux et couleurs - 2 = Ivoire clair; ...de matériaux et couleurs = Gris lumière
Enveloppe 424003 | Niveau 1 | Enveloppe | 424003 | 366 | 9000 | 1908701706 | 1977773087 | 0 | 1 | 0688 | 04 | Niveau 1 | no | rectangle | 46.5244 | 376.102 | 0.0128504 | 179.571 | 376.102 | 359.571 | HAUT Niveau 1 (Niveau 2 13545) | 3.90799e-12 | <aucun> | Niveau 1 (Niveau 1 2343) | <aucun> | 46.5 | 46.5 | 376.1 | 376.1 | 400 | 400 | 400 | 17500 | 160000 | Gris lumière | Ivoire clair | 157481 | 157481 | 9 | 376.102 | 418.72 | 17497.9 | 17497.9 | ...de stratigraphies = default; ...de matériaux et couleurs - 1 = Ivoire clair; ...de matériaux et couleurs - 2 = Ivoire clair; ...de matériaux et couleurs = Gris lumière
Enveloppe 423812 | Niveau 1 | Enveloppe | 423812 | 366 | 9000 | 1908701706 | 1977773087 | 1 | 1 | 0685 | 04 | Niveau 1 | no | rectangle | 47.4658 | 376.102 | 0.0128504 | 0.16417 | 376.102 | 180.164 | HAUT Niveau 1 (Niveau 2 13545) | 3.19744e-12 | <aucun> | Niveau 1 (Niveau 1 2343) | <aucun> | 47.5 | 47.5 | 376.1 | 376.1 | 400 | 400 | 400 | 17900 | 160000 | Gris lumière | Ivoire clair | 160668 | 160668 | 9 | 376.102 | 427.193 | 17852 | 17852 | ...de stratigraphies = default; ...de matériaux et couleurs - 1 = Ivoire clair; ...de matériaux et couleurs - 2 = Ivoire clair; ...de matériaux et couleurs = Gris lumière
Enveloppe 423877 | Niveau 1 | Enveloppe | 423877 | 366 | 9000 | 1908701706 | 1977773087 | 0 | 1 | 0686 | 04 | Niveau 1 | no | rectangle | 46.9381 | 376.102 | 0.0128504 | 179.389 | 376.102 | 359.389 | HAUT Niveau 1 (Niveau 2 13545) | 3.19744e-12 | <aucun> | Niveau 1 (Niveau 1 2343) | <aucun> | 46.9 | 46.9 | 376.1 | 376.1 | 400 | 400 | 400 | 17600 | 160000 | Gris lumière | Ivoire clair | 158882 | 158882 | 9 | 376.102 | 422.443 | 17653.5 | 17653.5 | ...de stratigraphies = default; ...de matériaux et couleurs - 1 = Ivoire clair; ...de matériaux et couleurs - 2 = Ivoire clair; ...de matériaux et couleurs = Gris lumière
Enveloppe 424066 | Niveau 1 | Enveloppe | 424066 | 366 | 9000 | 1908701706 | 1977773087 | 1 | 1 | 0689 | 04 | Niveau 1 | no | rectangle | 71.4952 | 376.102 | 0.0128504 | 0.453901 | 376.102 | 180.454 | HAUT Niveau 1 (Niveau 2 13545) | 4.26326e-12 | <aucun> | Niveau 1 (Niveau 1 2343) | <aucun> | 71.5 | 71.5 | 376.1 | 376.1 | 600 | 600 | 600 | 26900 | 240000 | Gris lumière | Ivoire clair | 242005 | 242005 | 9 | 376.102 | 643.456 | 26889.5 | 26889.5 | ...de stratigraphies = default; ...de matériaux et couleurs - 1 = Ivoire clair; ...de matériaux et couleurs - 2 = Ivoire clair; ...de matériaux et couleurs = Gris lumière
Enveloppe 424174 | Niveau 1 | Enveloppe | 424174 | 366 | 9000 | 1908701706 | 1977773087 | 1 | 1 | 0692 | 04 | Niveau 1 | no | rectangle | 123.437 | 376.102 | 0.0128504 | 0.0371683 | 376.102 | 180.037 | HAUT Niveau 1 (Niveau 2 13545) | 4.61853e-12 | <aucun> | Niveau 1 (Niveau 1 2343) | <aucun> | 123.4 | 123.4 | 376.1 | 376.1 | 1100 | 1100 | 1100 | 46400 | 420000 | Gris lumière | Ivoire clair | 417824 | 417824 | 9 | 376.102 | 1110.93 | 46424.9 | 46424.9 | ...de stratigraphies = default; ...de matériaux et couleurs - 1 = Ivoire clair; ...de matériaux et couleurs - 2 = Ivoire clair; ...de matériaux et couleurs = Gris lumière
Enveloppe 424197 | Niveau 1 | Enveloppe | 424197 | 366 | 9000 | 1908701706 | 1977773087 | 1 | 1 | 0693 | 04 | Niveau 1 | no | rectangle | 127.182 | 376.102 | 0.0128504 | 0.0371683 | 376.102 | 180.037 | HAUT Niveau 1 (Niveau 2 13545) | 4.61853e-12 | <aucun> | Niveau 1 (Niveau 1 2343) | <aucun> | 127.2 | 127.2 | 376.1 | 376.1 | 1100 | 1100 | 1100 | 47800 | 430000 | Gris lumière | Ivoire clair | 430501 | 430501 | 9 | 376.102 | 1144.64 | 47833.5 | 47833.5 | ...de stratigraphies = default; ...de matériaux et couleurs - 1 = Ivoire clair; ...de matériaux et couleurs - 2 = Ivoire clair; ...de matériaux et couleurs = Gris lumière
Enveloppe 424129 | Niveau 1 | Enveloppe | 424129 | 366 | 9000 | 1908701706 | 1977773087 | 0 | 1 | 0690 | 04 | Niveau 1 | no | rectangle | 190.782 | 376.102 | 0.0128504 | 89.5056 | 376.102 | 269.506 | HAUT Niveau 1 (Niveau 2 13545) | 4.26326e-12 | <aucun> | Niveau 1 (Niveau 1 2343) | <aucun> | 190.8 | 190.8 | 376.1 | 376.1 | 1700 | 1700 | 1700 | 71800 | 650000 | Gris lumière | Ivoire clair | 645782 | 409521 | 9 | 376.102 | 1717.04 | 71753.6 | 45502.3 | ...de stratigraphies = default; ...de matériaux et couleurs - 1 = Ivoire clair; ...de matériaux et couleurs - 2 = Ivoire clair; ...de matériaux et couleurs = Gris lumière
Enveloppe 424151 | Niveau 1 | Enveloppe | 424151 | 366 | 9000 | 1908701706 | 1977773087 | 0 | 1 | 0691 | 04 | Niveau 1 | no | rectangle | 63.9908 | 376.102 | 0.0128504 | 88.5135 | 376.102 | 268.513 | HAUT Niveau 1 (Niveau 2 13545) | 4.26326e-12 | <aucun> | Niveau 1 (Niveau 1 2343) | <aucun> | 64 | 64 | 376.1 | 376.1 | 600 | 600 | 600 | 24100 | 220000 | Gris lumière | Ivoire clair | 216604 | 216604 | 9 | 376.102 | 575.917 | 24067.1 | 24067.1 | ...de stratigraphies = default; ...de matériaux et couleurs - 1 = Ivoire clair; ...de matériaux et couleurs - 2 = Ivoire clair; ...de matériaux et couleurs = Gris lumière
Enveloppe 750970 | Niveau 1 | Enveloppe | 750970 | 366 | 9000 | 1977773087 | 1977773087 | 1 | 0 | 1091 | 04 | Niveau 1 | no | rectangle | 36.6763 | 376.102 | 0.0128504 | 0.264755 | 376.102 | 180.265 | HAUT Niveau 1 (Niveau 2 13545) | 8.52651e-12 | <aucun> | Niveau 1 (Niveau 1 2343) | <aucun> | 36.7 | 36.7 | 376.1 | 376.1 | 300 | 300 | 300 | 13800 | 120000 | Ivoire clair | Ivoire clair | 124146 | 124146 | 9 | 376.102 | 330.087 | 13794.1 | 13794.1 | ...de stratigraphies = default; ...de matériaux et couleurs = Ivoire clair; ...de matériaux et couleurs - 1 = Ivoire clair; ...de matériaux et couleurs - 2 = Ivoire clair
Enveloppe 751070 | Niveau 1 | Enveloppe | 751070 | 366 | 9000 | 1977773087 | 1977773087 | 1 | 0 | 1092 | 04 | Niveau 1 | no | rectangle | 31.6455 | 376.102 | 0.0128504 | 85.1338 | 376.102 | 265.134 | HAUT Niveau 1 (Niveau 2 13545) | 8.52651e-12 | <aucun> | Niveau 1 (Niveau 1 2343) | <aucun> | 31.6 | 31.6 | 376.1 | 376.1 | 300 | 300 | 300 | 11900 | 110000 | Ivoire clair | Ivoire clair | 107118 | 107118 | 9 | 376.102 | 284.81 | 11901.9 | 11901.9 | ...de stratigraphies = default; ...de matériaux et couleurs = Ivoire clair; ...de matériaux et couleurs - 1 = Ivoire clair; ...de matériaux et couleurs - 2 = Ivoire clair
Enveloppe 718700 | Niveau 1 | Enveloppe | 718700 | 366 | 9000 | 1977773087 | 1977773087 | 0 | 1 | 1046 | 04 | Niveau 1 | no | rectangle | 34.636 | 356.102 | 0.0128504 | 90.5287 | 356.102 | 270.529 | HAUT Niveau 1 (Niveau 2 13545) | -20 | <aucun> | Niveau 1 (Niveau 1 2343) | <aucun> | 34.6 | 34.6 | 356.1 | 356.1 | 300 | 300 | 300 | 12300 | 110000 | Ivoire clair | Ivoire clair | 111005 | 111005 | 9 | 356.102 | 311.724 | 12333.9 | 12333.9 | ...de stratigraphies = default; ...de matériaux et couleurs = Ivoire clair; ...de matériaux et couleurs - 1 = Ivoire clair; ...de matériaux et couleurs - 2 = Ivoire clair
Enveloppe 718734 | Niveau 1 | Enveloppe | 718734 | 366 | 9000 | 1977773087 | 1977773087 | 0 | 1 | 1047 | 04 | Niveau 1 | no | rectangle | 172.875 | 356.102 | 0.0128504 | 90.4554 | 356.102 | 270.455 | HAUT Niveau 1 (Niveau 2 13545) | -20 | <aucun> | Niveau 1 (Niveau 1 2343) | <aucun> | 172.9 | 172.9 | 356.1 | 356.1 | 1600 | 1600 | 1600 | 61600 | 550000 | Ivoire clair | Ivoire clair | 554050 | 222755 | 9 | 356.102 | 1555.87 | 61561.2 | 24750.5 | ...de stratigraphies = default; ...de matériaux et couleurs = Ivoire clair; ...de matériaux et couleurs - 1 = Ivoire clair; ...de matériaux et couleurs - 2 = Ivoire clair
Enveloppe 724235 | Niveau 1 | Enveloppe | 724235 | 366 | 9000 | 1977773087 | 1977773087 | 0 | 1 | 1060 | 04 | Niveau 1 | no | rectangle | 43.5269 | 376.102 | 0.0128504 | 172.284 | 376.102 | 352.284 | HAUT Niveau 1 (Niveau 2 13545) | 8.17124e-12 | <aucun> | Niveau 1 (Niveau 1 2343) | <aucun> | 43.5 | 43.5 | 376.1 | 376.1 | 400 | 400 | 400 | 16400 | 150000 | Ivoire clair | Ivoire clair | 147335 | 147335 | 9 | 376.102 | 391.742 | 16370.6 | 16370.6 | ...de stratigraphies = default; ...de matériaux et couleurs = Ivoire clair; ...de matériaux et couleurs - 1 = Ivoire clair; ...de matériaux et couleurs - 2 = Ivoire clair
Enveloppe 1528572 | Niveau 1 | Enveloppe | 1528572 | 366 | 9000 | 1977773087 | 1977773087 | 0 | 1 | 1162 | 04 | Niveau 1 | no | rectangle | 22.6887 | 376.102 | 0.0128504 | 90.2916 | 376.102 | 270.292 | HAUT Niveau 1 (Niveau 2 13545) | 1.10134e-11 | <aucun> | Niveau 1 (Niveau 1 2343) | <aucun> | 22.7 | 22.7 | 376.1 | 376.1 | 200 | 200 | 200 | 8500 | 80000 | Ivoire clair | Ivoire clair | 76799.4 | 76799.4 | 9 | 376.102 | 204.198 | 8533.26 | 8533.26 | ...de stratigraphies = default; ...de matériaux et couleurs = Ivoire clair; ...de matériaux et couleurs - 1 = Ivoire clair; ...de matériaux et couleurs - 2 = Ivoire clair
Enveloppe 776368 | Niveau 1 | Enveloppe | 776368 | 366 | 9000 | 1977773087 | 1977773087 | 0 | 0 | 1122 | 04 | Niveau 1 | no | rectangle | 36.0182 | 376.102 | 0.0128504 | 86.392 | 376.102 | 266.392 | HAUT Niveau 1 (Niveau 2 13545) | 9.9476e-12 | <aucun> | Niveau 1 (Niveau 1 2343) | <aucun> | 36 | 36 | 376.1 | 376.1 | 300 | 300 | 300 | 13500 | 120000 | Ivoire clair | Ivoire clair | 121919 | 121919 | 9 | 376.102 | 324.164 | 13546.5 | 13546.5 | ...de stratigraphies = default; ...de matériaux et couleurs = Ivoire clair; ...de matériaux et couleurs - 1 = Ivoire clair; ...de matériaux et couleurs - 2 = Ivoire clair
Enveloppe 776312 | Niveau 1 | Enveloppe | 776312 | 366 | 9000 | 1977773087 | 1977773087 | 1 | 0 | 1120 | 04 | Niveau 1 | no | rectangle | 36.1635 | 376.102 | 0.0128504 | 95.66 | 376.102 | 275.66 | HAUT Niveau 1 (Niveau 2 13545) | 9.9476e-12 | <aucun> | Niveau 1 (Niveau 1 2343) | <aucun> | 36.2 | 36.2 | 376.1 | 376.1 | 300 | 300 | 300 | 13600 | 120000 | Ivoire clair | Ivoire clair | 122410 | 122410 | 9 | 376.102 | 325.471 | 13601.2 | 13601.2 | ...de stratigraphies = default; ...de matériaux et couleurs = Ivoire clair; ...de matériaux et couleurs - 1 = Ivoire clair; ...de matériaux et couleurs - 2 = Ivoire clair
Enveloppe 776544 | Niveau 1 | Enveloppe | 776544 | 366 | 9000 | 1977773087 | 1977773087 | 1 | 0 | 1124 | 04 | Niveau 1 | no | rectangle | 26.0013 | 376.102 | 0.0128504 | 179.313 | 376.102 | 359.313 | HAUT Niveau 1 (Niveau 2 13545) | 1.03029e-11 | <aucun> | Niveau 1 (Niveau 1 2343) | <aucun> | 26 | 26 | 376.1 | 376.1 | 200 | 200 | 200 | 9800 | 90000 | Ivoire clair | Ivoire clair | 88012.4 | 88012.4 | 9 | 376.102 | 234.012 | 9779.15 | 9779.15 | ...de stratigraphies = default; ...de matériaux et couleurs = Ivoire clair; ...de matériaux et couleurs - 1 = Ivoire clair; ...de matériaux et couleurs - 2 = Ivoire clair
Enveloppe 776754 | Niveau 1 | Enveloppe | 776754 | 366 | 9000 | 1977773087 | 1977773087 | 0 | 0 | 1127 | 04 | Niveau 1 | no | rectangle | 119.712 | 376.102 | 0.0128504 | 89.889 | 376.102 | 269.889 | HAUT Niveau 1 (Niveau 2 13545) | 0 | <aucun> | Niveau 1 (Niveau 1 2343) | <aucun> | 119.7 | 119.7 | 376.1 | 376.1 | 1100 | 1100 | 1100 | 45000 | 410000 | Ivoire clair | Ivoire clair | 405214 | 192683 | 9 | 376.102 | 1077.41 | 45023.8 | 21409.3 | ...de stratigraphies = default; ...de matériaux et couleurs = Ivoire clair; ...de matériaux et couleurs - 1 = Ivoire clair; ...de matériaux et couleurs - 2 = Ivoire clair
Enveloppe 777076 | Niveau 1 | Enveloppe | 777076 | 366 | 9000 | 1977773087 | 1977773087 | 1 | 0 | 1128 | 04 | Niveau 1 | no | rectangle | 74.4041 | 376.102 | 0.0128504 | 89.8351 | 376.102 | 269.835 | HAUT Niveau 1 (Niveau 2 13545) | 1.03029e-11 | <aucun> | Niveau 1 (Niveau 1 2343) | <aucun> | 74.4 | 74.4 | 376.1 | 376.1 | 700 | 700 | 700 | 28000 | 250000 | Ivoire clair | Ivoire clair | 251852 | 251852 | 9 | 376.102 | 669.637 | 27983.6 | 27983.6 | ...de stratigraphies = default; ...de matériaux et couleurs = Ivoire clair; ...de matériaux et couleurs - 1 = Ivoire clair; ...de matériaux et couleurs - 2 = Ivoire clair
Enveloppe 776717 | Niveau 1 | Enveloppe | 776717 | 366 | 9000 | 1977773087 | 1977773087 | 1 | 0 | 1125 | 04 | Niveau 1 | no | rectangle | 57.4603 | 376.102 | 0.0128504 | 89.8351 | 376.102 | 269.835 | HAUT Niveau 1 (Niveau 2 13545) | 1.03029e-11 | <aucun> | Niveau 1 (Niveau 1 2343) | <aucun> | 57.5 | 57.5 | 376.1 | 376.1 | 500 | 500 | 500 | 21600 | 190000 | Ivoire clair | Ivoire clair | 194498 | 194498 | 9 | 376.102 | 517.142 | 21610.9 | 21610.9 | ...de stratigraphies = default; ...de matériaux et couleurs = Ivoire clair; ...de matériaux et couleurs - 1 = Ivoire clair; ...de matériaux et couleurs - 2 = Ivoire clair
Enveloppe 776753 | Niveau 1 | Enveloppe | 776753 | 366 | 9000 | 1977773087 | 1977773087 | 0 | 0 | 1126 | 04 | Niveau 1 | no | rectangle | 26.1072 | 376.102 | 0.0128504 | 179.962 | 376.102 | 359.962 | HAUT Niveau 1 (Niveau 2 13545) | 1.03029e-11 | <aucun> | Niveau 1 (Niveau 1 2343) | <aucun> | 26.1 | 26.1 | 376.1 | 376.1 | 200 | 200 | 200 | 9800 | 90000 | Ivoire clair | Ivoire clair | 88370.9 | 88370.9 | 9 | 376.102 | 234.965 | 9818.99 | 9818.99 | ...de stratigraphies = default; ...de matériaux et couleurs = Ivoire clair; ...de matériaux et couleurs - 1 = Ivoire clair; ...de matériaux et couleurs - 2 = Ivoire clair
Enveloppe 775823 | Niveau 1 | Enveloppe | 775823 | 366 | 9000 | 1977773087 | 1977773087 | 1 | 0 | 1114 | 04 | Niveau 1 | no | rectangle | 135.601 | 376.102 | 0.0128504 | 179.927 | 376.102 | 359.927 | HAUT Niveau 1 (Niveau 2 13545) | 9.59233e-12 | <aucun> | Niveau 1 (Niveau 1 2343) | <aucun> | 135.6 | 135.6 | 376.1 | 376.1 | 1200 | 1200 | 1200 | 51000 | 460000 | Ivoire clair | Ivoire clair | 458999 | 458999 | 9 | 376.102 | 1220.41 | 50999.8 | 50999.8 | ...de stratigraphies = default; ...de matériaux et couleurs = Ivoire clair; ...de matériaux et couleurs - 1 = Ivoire clair; ...de matériaux et couleurs - 2 = Ivoire clair
Enveloppe 775859 | Niveau 1 | Enveloppe | 775859 | 366 | 9000 | 1977773087 | 1977773087 | 0 | 0 | 1115 | 04 | Niveau 1 | no | rectangle | 37.1195 | 376.102 | 0.0128504 | 85.6324 | 376.102 | 265.632 | HAUT Niveau 1 (Niveau 2 13545) | 9.59233e-12 | <aucun> | Niveau 1 (Niveau 1 2343) | <aucun> | 37.1 | 37.1 | 376.1 | 376.1 | 300 | 300 | 300 | 14000 | 130000 | Ivoire clair | Ivoire clair | 125646 | 125646 | 9 | 376.102 | 334.075 | 13960.7 | 13960.7 | ...de stratigraphies = default; ...de matériaux et couleurs = Ivoire clair; ...de matériaux et couleurs - 1 = Ivoire clair; ...de matériaux et couleurs - 2 = Ivoire clair
Enveloppe 776051 | Niveau 1 | Enveloppe | 776051 | 366 | 9000 | 1977773087 | 1977773087 | 1 | 0 | 1118 | 04 | Niveau 1 | no | rectangle | 37.1167 | 376.102 | 0.0128504 | 94.9028 | 376.102 | 274.903 | HAUT Niveau 1 (Niveau 2 13545) | 9.9476e-12 | <aucun> | Niveau 1 (Niveau 1 2343) | <aucun> | 37.1 | 37.1 | 376.1 | 376.1 | 300 | 300 | 300 | 14000 | 130000 | Ivoire clair | Ivoire clair | 125637 | 125637 | 9 | 376.102 | 334.05 | 13959.7 | 13959.7 | ...de stratigraphies = default; ...de matériaux et couleurs = Ivoire clair; ...de matériaux et couleurs - 1 = Ivoire clair; ...de matériaux et couleurs - 2 = Ivoire clair
Enveloppe 776215 | Niveau 1 | Enveloppe | 776215 | 366 | 9000 | 1977773087 | 1977773087 | 0 | 0 | 1119 | 04 | Niveau 1 | no | rectangle | 36.4953 | 376.102 | 0.0128504 | 0.257431 | 376.102 | 180.257 | HAUT Niveau 1 (Niveau 2 13545) | 9.9476e-12 | <aucun> | Niveau 1 (Niveau 1 2343) | <aucun> | 36.5 | 36.5 | 376.1 | 376.1 | 300 | 300 | 300 | 13700 | 120000 | Ivoire clair | Ivoire clair | 123534 | 123534 | 9 | 376.102 | 328.457 | 13725.9 | 13725.9 | ...de stratigraphies = default; ...de matériaux et couleurs = Ivoire clair; ...de matériaux et couleurs - 1 = Ivoire clair; ...de matériaux et couleurs - 2 = Ivoire clair
Enveloppe 776015 | Niveau 1 | Enveloppe | 776015 | 366 | 9000 | 1977773087 | 1977773087 | 0 | 0 | 1117 | 04 | Niveau 1 | no | rectangle | 131.189 | 376.102 | 0.0128504 | 0.257431 | 376.102 | 180.257 | HAUT Niveau 1 (Niveau 2 13545) | 9.9476e-12 | <aucun> | Niveau 1 (Niveau 1 2343) | <aucun> | 131.2 | 131.2 | 376.1 | 376.1 | 1200 | 1200 | 1200 | 49300 | 440000 | Ivoire clair | Ivoire clair | 444064 | 444064 | 9 | 376.102 | 1180.7 | 49340.4 | 49340.4 | ...de stratigraphies = default; ...de matériaux et couleurs = Ivoire clair; ...de matériaux et couleurs - 1 = Ivoire clair; ...de matériaux et couleurs - 2 = Ivoire clair
Enveloppe 596929 | Niveau 1 | Enveloppe | 596929 | 366 | 9000 | 1977773087 | 1977773087 | 0 | 1 | 0939 | 04 | Niveau 1 | no | rectangle | 31.1006 | 376.102 | 0.0128504 | 4.78165 | 376.102 | 184.782 | HAUT Niveau 1 (Niveau 2 13545) | 0 | <aucun> | Niveau 1 (Niveau 1 2343) | <aucun> | 31.1 | 31.1 | 376.1 | 376.1 | 300 | 300 | 300 | 11700 | 110000 | Ivoire clair | Ivoire clair | 105273 | 105273 | 9 | 376.102 | 279.906 | 11697 | 11697 | ...de stratigraphies = default; ...de matériaux et couleurs = Ivoire clair; ...de matériaux et couleurs - 1 = Ivoire clair; ...de matériaux et couleurs - 2 = Ivoire clair
Enveloppe 597120 | Niveau 1 | Enveloppe | 597120 | 366 | 9000 | 1977773087 | 1977773087 | 0 | 1 | 0942 | 04 | Niveau 1 | no | rectangle | 184.77 | 376.102 | 0.0128504 | 90.6447 | 376.102 | 270.645 | HAUT Niveau 1 (Niveau 2 13545) | 0 | <aucun> | Niveau 1 (Niveau 1 2343) | <aucun> | 184.8 | 184.8 | 376.1 | 376.1 | 1700 | 1700 | 1700 | 69500 | 630000 | Ivoire clair | Ivoire clair | 625432 | 625432 | 9 | 376.102 | 1662.93 | 69492.4 | 69492.4 | ...de stratigraphies = default; ...de matériaux et couleurs = Ivoire clair; ...de matériaux et couleurs - 1 = Ivoire clair; ...de matériaux et couleurs - 2 = Ivoire clair
Enveloppe 597122 | Niveau 1 | Enveloppe | 597122 | 366 | 9000 | 1977773087 | 1977773087 | 1 | 1 | 0943 | 04 | Niveau 1 | no | rectangle | 117.416 | 376.102 | 0.0128504 | 90.171 | 376.102 | 270.171 | HAUT Niveau 1 (Niveau 2 13545) | 0 | <aucun> | Niveau 1 (Niveau 1 2343) | <aucun> | 117.4 | 117.4 | 376.1 | 376.1 | 1100 | 1100 | 1100 | 44200 | 400000 | Ivoire clair | Ivoire clair | 397445 | 159615 | 9 | 376.102 | 1056.75 | 44160.6 | 17735 | ...de stratigraphies = default; ...de matériaux et couleurs = Ivoire clair; ...de matériaux et couleurs - 1 = Ivoire clair; ...de matériaux et couleurs - 2 = Ivoire clair
Enveloppe 597024 | Niveau 1 | Enveloppe | 597024 | 366 | 9000 | 1977773087 | 1977773087 | 0 | 1 | 0940 | 04 | Niveau 1 | no | rectangle | 180.512 | 376.102 | 0.0128504 | 90.1709 | 376.102 | 270.171 | HAUT Niveau 1 (Niveau 2 13545) | 0 | <aucun> | Niveau 1 (Niveau 1 2343) | <aucun> | 180.5 | 180.5 | 376.1 | 376.1 | 1600 | 1600 | 1600 | 67900 | 610000 | Ivoire clair | Ivoire clair | 611020 | 611020 | 9 | 376.102 | 1624.61 | 67891.1 | 67891.1 | ...de stratigraphies = default; ...de matériaux et couleurs = Ivoire clair; ...de matériaux et couleurs - 1 = Ivoire clair; ...de matériaux et couleurs - 2 = Ivoire clair
Enveloppe 597027 | Niveau 1 | Enveloppe | 597027 | 366 | 9000 | 1977773087 | 1977773087 | 0 | 1 | 0941 | 04 | Niveau 1 | no | rectangle | 31.1006 | 376.102 | 0.0128504 | 175.56 | 376.102 | 355.56 | HAUT Niveau 1 (Niveau 2 13545) | 0 | <aucun> | Niveau 1 (Niveau 1 2343) | <aucun> | 31.1 | 31.1 | 376.1 | 376.1 | 300 | 300 | 300 | 11700 | 110000 | Ivoire clair | Ivoire clair | 105273 | 105273 | 9 | 376.102 | 279.906 | 11697 | 11697 | ...de stratigraphies = default; ...de matériaux et couleurs = Ivoire clair; ...de matériaux et couleurs - 1 = Ivoire clair; ...de matériaux et couleurs - 2 = Ivoire clair
Enveloppe 598906 | Niveau 1 | Enveloppe | 598906 | 366 | 9000 | 1977773087 | 1977773087 | 1 | 0 | 0955 | 04 | Niveau 1 | yes | rectangle | 147.047 | 376.102 | 0.0128504 | 0.120926 | 376.102 | 180.121 | HAUT Niveau 1 (Niveau 2 13545) | 0 | <aucun> | Niveau 1 (Niveau 1 2343) | <aucun> | 147 | 147 | 376.1 | 376.1 | 1300 | 1300 | 1300 | 55300 | 500000 | Ivoire clair | Ivoire clair | 497742 | 497742 | 9 | 376.102 | 1323.42 | 55304.7 | 55304.7 | ...de stratigraphies = default; ...de matériaux et couleurs = Ivoire clair; ...de matériaux et couleurs - 1 = Ivoire clair; ...de matériaux et couleurs - 2 = Ivoire clair
Enveloppe 598955 | Niveau 1 | Enveloppe | 598955 | 366 | 9000 | 1977773087 | 1977773087 | 0 | 0 | 0956 | 04 | Niveau 1 | no | rectangle | 115.743 | 376.102 | 0.0128504 | 0.905984 | 376.102 | 180.906 | HAUT Niveau 1 (Niveau 2 13545) | 0 | <aucun> | Niveau 1 (Niveau 1 2343) | <aucun> | 115.7 | 115.7 | 376.1 | 376.1 | 1000 | 1000 | 1000 | 43500 | 390000 | Ivoire clair | Ivoire clair | 391781 | 141198 | 9 | 376.102 | 1041.69 | 43531.2 | 15688.7 | ...de stratigraphies = default; ...de matériaux et couleurs = Ivoire clair; ...de matériaux et couleurs - 1 = Ivoire clair; ...de matériaux et couleurs - 2 = Ivoire clair
Enveloppe 598638 | Niveau 1 | Enveloppe | 598638 | 366 | 9000 | 1977773087 | 1977773087 | 0 | 0 | 0953 | 04 | Niveau 1 | yes | rectangle | 42.6151 | 376.102 | 0.0128504 | 0.935579 | 376.102 | 180.936 | HAUT Niveau 1 (Niveau 2 13545) | 0 | <aucun> | Niveau 1 (Niveau 1 2343) | <aucun> | 42.6 | 42.6 | 376.1 | 376.1 | 400 | 400 | 400 | 16000 | 140000 | Ivoire clair | Ivoire clair | 144249 | 144249 | 9 | 376.102 | 383.535 | 16027.6 | 16027.6 | ...de stratigraphies = default; ...de matériaux et couleurs = Ivoire clair; ...de matériaux et couleurs - 1 = Ivoire clair; ...de matériaux et couleurs - 2 = Ivoire clair
Enveloppe 598813 | Niveau 1 | Enveloppe | 598813 | 366 | 9000 | 1977773087 | 1977773087 | 0 | 0 | 0954 | 04 | Niveau 1 | yes | rectangle | 34.8472 | 376.102 | 0.0128504 | 94.7325 | 376.102 | 274.732 | HAUT Niveau 1 (Niveau 2 13545) | 0 | <aucun> | Niveau 1 (Niveau 1 2343) | <aucun> | 34.8 | 34.8 | 376.1 | 376.1 | 300 | 300 | 300 | 13100 | 120000 | Ivoire clair | Ivoire clair | 117955 | 117955 | 9 | 376.102 | 313.625 | 13106.1 | 13106.1 | ...de stratigraphies = default; ...de matériaux et couleurs = Ivoire clair; ...de matériaux et couleurs - 1 = Ivoire clair; ...de matériaux et couleurs - 2 = Ivoire clair
Enveloppe 599147 | Niveau 1 | Enveloppe | 599147 | 366 | 9000 | 1977773087 | 1977773087 | 1 | 0 | 0957 | 04 | Niveau 1 | yes | rectangle | 32.8681 | 376.102 | 0.0128504 | 86.4633 | 376.102 | 266.463 | HAUT Niveau 1 (Niveau 2 13545) | 0 | <aucun> | Niveau 1 (Niveau 1 2343) | <aucun> | 32.9 | 32.9 | 376.1 | 376.1 | 300 | 300 | 300 | 12400 | 110000 | Ivoire clair | Ivoire clair | 111256 | 111256 | 9 | 376.102 | 295.813 | 12361.8 | 12361.8 | ...de stratigraphies = default; ...de matériaux et couleurs = Ivoire clair; ...de matériaux et couleurs - 1 = Ivoire clair; ...de matériaux et couleurs - 2 = Ivoire clair
Enveloppe 599598 | Niveau 1 | Enveloppe | 599598 | 366 | 9000 | 1977773087 | 1977773087 | 1 | 0 | 0960 | 04 | Niveau 1 | yes | rectangle | 152.492 | 376.102 | 0.0128504 | 0.120926 | 376.102 | 180.121 | HAUT Niveau 1 (Niveau 2 13545) | 0 | <aucun> | Niveau 1 (Niveau 1 2343) | <aucun> | 152.5 | 152.5 | 376.1 | 376.1 | 1400 | 1400 | 1400 | 57400 | 520000 | Ivoire clair | Ivoire clair | 516174 | 516174 | 9 | 376.102 | 1372.43 | 57352.7 | 57352.7 | ...de stratigraphies = default; ...de matériaux et couleurs = Ivoire clair; ...de matériaux et couleurs - 1 = Ivoire clair; ...de matériaux et couleurs - 2 = Ivoire clair
Enveloppe 599631 | Niveau 1 | Enveloppe | 599631 | 366 | 9000 | 1977773087 | 1977773087 | 0 | 0 | 0961 | 04 | Niveau 1 | yes | rectangle | 38.8345 | 376.102 | 0.0128504 | 95.642 | 376.102 | 275.642 | HAUT Niveau 1 (Niveau 2 13545) | 0 | <aucun> | Niveau 1 (Niveau 1 2343) | <aucun> | 38.8 | 38.8 | 376.1 | 376.1 | 300 | 300 | 300 | 14600 | 130000 | Ivoire clair | Ivoire clair | 131452 | 131452 | 9 | 376.102 | 349.51 | 14605.7 | 14605.7 | ...de stratigraphies = default; ...de matériaux et couleurs = Ivoire clair; ...de matériaux et couleurs - 1 = Ivoire clair; ...de matériaux et couleurs - 2 = Ivoire clair
Enveloppe 599253 | Niveau 1 | Enveloppe | 599253 | 366 | 9000 | 1977773087 | 1977773087 | 1 | 0 | 0958 | 04 | Niveau 1 | yes | rectangle | 92.3627 | 376.102 | 0.0128504 | 0.120926 | 376.102 | 180.121 | HAUT Niveau 1 (Niveau 2 13545) | 0 | <aucun> | Niveau 1 (Niveau 1 2343) | <aucun> | 92.4 | 92.4 | 376.1 | 376.1 | 800 | 800 | 800 | 34800 | 310000 | Ivoire clair | Ivoire clair | 312640 | 312640 | 9 | 376.102 | 831.265 | 34737.8 | 34737.8 | ...de stratigraphies = default; ...de matériaux et couleurs = Ivoire clair; ...de matériaux et couleurs - 1 = Ivoire clair; ...de matériaux et couleurs - 2 = Ivoire clair
Enveloppe 599505 | Niveau 1 | Enveloppe | 599505 | 366 | 9000 | 1977773087 | 1977773087 | 1 | 0 | 0959 | 04 | Niveau 1 | yes | rectangle | 40.9064 | 376.102 | 0.0128504 | 86.4202 | 376.102 | 266.42 | HAUT Niveau 1 (Niveau 2 13545) | 0 | <aucun> | Niveau 1 (Niveau 1 2343) | <aucun> | 40.9 | 40.9 | 376.1 | 376.1 | 400 | 400 | 400 | 15400 | 140000 | Ivoire clair | Ivoire clair | 138465 | 138465 | 9 | 376.102 | 368.157 | 15385 | 15385 | ...de stratigraphies = default; ...de matériaux et couleurs = Ivoire clair; ...de matériaux et couleurs - 1 = Ivoire clair; ...de matériaux et couleurs - 2 = Ivoire clair
Enveloppe 597556 | Niveau 1 | Enveloppe | 597556 | 366 | 9000 | 1977773087 | 1977773087 | 1 | 1 | 0947 | 04 | Niveau 1 | no | rectangle | 258.648 | 376.102 | 0.0128504 | 0.264755 | 376.102 | 180.265 | HAUT Niveau 1 (Niveau 2 13545) | 0 | <aucun> | Niveau 1 (Niveau 1 2343) | <aucun> | 258.6 | 258.6 | 376.1 | 376.1 | 2300 | 2300 | 2300 | 97300 | 880000 | Ivoire clair | Ivoire clair | 875501 | 875501 | 9 | 376.102 | 2327.83 | 97277.9 | 97277.9 | ...de stratigraphies = default; ...de matériaux et couleurs = Ivoire clair; ...de matériaux et couleurs - 1 = Ivoire clair; ...de matériaux et couleurs - 2 = Ivoire clair
Enveloppe 597427 | Niveau 1 | Enveloppe | 597427 | 366 | 9000 | 1977773087 | 1977773087 | 1 | 1 | 0944 | 04 | Niveau 1 | no | rectangle | 256.276 | 376.102 | 0.0128504 | 0.399987 | 376.102 | 180.4 | HAUT Niveau 1 (Niveau 2 13545) | 0 | <aucun> | Niveau 1 (Niveau 1 2343) | <aucun> | 256.3 | 256.3 | 376.1 | 376.1 | 2300 | 2300 | 2300 | 96400 | 870000 | Ivoire clair | Ivoire clair | 867472 | 867472 | 9 | 376.102 | 2306.48 | 96385.8 | 96385.8 | ...de stratigraphies = default; ...de matériaux et couleurs = Ivoire clair; ...de matériaux et couleurs - 1 = Ivoire clair; ...de matériaux et couleurs - 2 = Ivoire clair
Enveloppe 597462 | Niveau 1 | Enveloppe | 597462 | 366 | 9000 | 1977773087 | 1977773087 | 0 | 1 | 0945 | 04 | Niveau 1 | no | rectangle | 31.1324 | 376.102 | 0.0128504 | 95.471 | 376.102 | 275.471 | HAUT Niveau 1 (Niveau 2 13545) | 0 | <aucun> | Niveau 1 (Niveau 1 2343) | <aucun> | 31.1 | 31.1 | 376.1 | 376.1 | 300 | 300 | 300 | 11700 | 110000 | Ivoire clair | Ivoire clair | 105381 | 105381 | 9 | 376.102 | 280.192 | 11709 | 11709 | ...de stratigraphies = default; ...de matériaux et couleurs = Ivoire clair; ...de matériaux et couleurs - 1 = Ivoire clair; ...de matériaux et couleurs - 2 = Ivoire clair
Enveloppe 597590 | Niveau 1 | Enveloppe | 597590 | 366 | 9000 | 1977773087 | 1977773087 | 1 | 1 | 0948 | 04 | Niveau 1 | no | rectangle | 31.0709 | 376.102 | 0.0128504 | 83.5928 | 376.102 | 263.593 | HAUT Niveau 1 (Niveau 2 13545) | 0 | <aucun> | Niveau 1 (Niveau 1 2343) | <aucun> | 31.1 | 31.1 | 376.1 | 376.1 | 300 | 300 | 300 | 11700 | 110000 | Ivoire clair | Ivoire clair | 105172 | 105172 | 9 | 376.102 | 279.638 | 11685.8 | 11685.8 | ...de stratigraphies = default; ...de matériaux et couleurs = Ivoire clair; ...de matériaux et couleurs - 1 = Ivoire clair; ...de matériaux et couleurs - 2 = Ivoire clair
Enveloppe 598542 | Niveau 1 | Enveloppe | 598542 | 366 | 9000 | 1977773087 | 1977773087 | 1 | 0 | 0951 | 04 | Niveau 1 | yes | rectangle | 45.3145 | 376.102 | 0.0128504 | 0.366958 | 376.102 | 180.367 | HAUT Niveau 1 (Niveau 2 13545) | 0 | <aucun> | Niveau 1 (Niveau 1 2343) | <aucun> | 45.3 | 45.3 | 376.1 | 376.1 | 400 | 400 | 400 | 17000 | 150000 | Ivoire clair | Ivoire clair | 153386 | 153386 | 9 | 376.102 | 407.83 | 17042.9 | 17042.9 | ...de stratigraphies = default; ...de matériaux et couleurs = Ivoire clair; ...de matériaux et couleurs - 1 = Ivoire clair; ...de matériaux et couleurs - 2 = Ivoire clair
Enveloppe 597906 | Niveau 1 | Enveloppe | 597906 | 366 | 9000 | 1977773087 | 1977773087 | 0 | 0 | 0949 | 04 | Niveau 1 | yes | rectangle | 44.0568 | 376.102 | 0.0128504 | 0.439485 | 376.102 | 180.439 | HAUT Niveau 1 (Niveau 2 13545) | 0 | <aucun> | Niveau 1 (Niveau 1 2343) | <aucun> | 44.1 | 44.1 | 376.1 | 376.1 | 400 | 400 | 400 | 16600 | 150000 | Ivoire clair | Ivoire clair | 149129 | 149129 | 9 | 376.102 | 396.511 | 16569.9 | 16569.9 | ...de stratigraphies = default; ...de matériaux et couleurs = Ivoire clair; ...de matériaux et couleurs - 1 = Ivoire clair; ...de matériaux et couleurs - 2 = Ivoire clair
Enveloppe 598279 | Niveau 1 | Enveloppe | 598279 | 366 | 9000 | 1977773087 | 1977773087 | 0 | 0 | 0950 | 04 | Niveau 1 | yes | rectangle | 23.1097 | 376.102 | 0.0128504 | 90.8599 | 376.102 | 270.86 | HAUT Niveau 1 (Niveau 2 13545) | 0 | <aucun> | Niveau 1 (Niveau 1 2343) | <aucun> | 23.1 | 23.1 | 376.1 | 376.1 | 200 | 200 | 200 | 8700 | 80000 | Ivoire clair | Ivoire clair | 78224.5 | 78224.5 | 9 | 376.102 | 207.987 | 8691.61 | 8691.61 | ...de stratigraphies = default; ...de matériaux et couleurs = Ivoire clair; ...de matériaux et couleurs - 1 = Ivoire clair; ...de matériaux et couleurs - 2 = Ivoire clair
Enveloppe 601335 | Niveau 1 | Enveloppe | 601335 | 366 | 9000 | 1977773087 | 1977773087 | 1 | 0 | 0974 | 04 | Niveau 1 | yes | rectangle | 183.252 | 376.102 | 0.0128504 | 90.5267 | 376.102 | 270.527 | HAUT Niveau 1 (Niveau 2 13545) | 0 | <aucun> | Niveau 1 (Niveau 1 2343) | <aucun> | 183.3 | 183.3 | 376.1 | 376.1 | 1600 | 1600 | 1600 | 68900 | 620000 | Ivoire clair | Ivoire clair | 620294 | 620294 | 9 | 376.102 | 1649.27 | 68921.6 | 68921.6 | ...de stratigraphies = default; ...de matériaux et couleurs = Ivoire clair; ...de matériaux et couleurs - 1 = Ivoire clair; ...de matériaux et couleurs - 2 = Ivoire clair
Enveloppe 601371 | Niveau 1 | Enveloppe | 601371 | 366 | 9000 | 1977773087 | 1977773087 | 1 | 0 | 0975 | 04 | Niveau 1 | yes | rectangle | 25.9869 | 376.102 | 0.0128504 | 7.15582 | 376.102 | 187.156 | HAUT Niveau 1 (Niveau 2 13545) | 0 | <aucun> | Niveau 1 (Niveau 1 2343) | <aucun> | 26 | 26 | 376.1 | 376.1 | 200 | 200 | 200 | 9800 | 90000 | Ivoire clair | Ivoire clair | 87963.5 | 87963.5 | 9 | 376.102 | 233.882 | 9773.73 | 9773.73 | ...de stratigraphies = default; ...de matériaux et couleurs = Ivoire clair; ...de matériaux et couleurs - 1 = Ivoire clair; ...de matériaux et couleurs - 2 = Ivoire clair
Enveloppe 601097 | Niveau 1 | Enveloppe | 601097 | 366 | 9000 | 1977773087 | 1977773087 | 1 | 0 | 0972 | 04 | Niveau 1 | yes | rectangle | 183.676 | 376.102 | 0.0128504 | 0.506457 | 376.102 | 180.506 | HAUT Niveau 1 (Niveau 2 13545) | 0 | <aucun> | Niveau 1 (Niveau 1 2343) | <aucun> | 183.7 | 183.7 | 376.1 | 376.1 | 1700 | 1700 | 1700 | 69100 | 620000 | Ivoire clair | Ivoire clair | 621728 | 621728 | 9 | 376.102 | 1653.08 | 69080.9 | 69080.9 | ...de stratigraphies = default; ...de matériaux et couleurs = Ivoire clair; ...de matériaux et couleurs - 1 = Ivoire clair; ...de matériaux et couleurs - 2 = Ivoire clair
Enveloppe 601131 | Niveau 1 | Enveloppe | 601131 | 366 | 9000 | 1977773087 | 1977773087 | 1 | 0 | 0973 | 04 | Niveau 1 | no | rectangle | 36.0629 | 376.102 | 0.0128504 | 86.299 | 376.102 | 266.299 | HAUT Niveau 1 (Niveau 2 13545) | 0 | <aucun> | Niveau 1 (Niveau 1 2343) | <aucun> | 36.1 | 36.1 | 376.1 | 376.1 | 300 | 300 | 300 | 13600 | 120000 | Ivoire clair | Ivoire clair | 122070 | 122070 | 9 | 376.102 | 324.566 | 13563.3 | 13563.3 | ...de stratigraphies = default; ...de matériaux et couleurs = Ivoire clair; ...de matériaux et couleurs - 1 = Ivoire clair; ...de matériaux et couleurs - 2 = Ivoire clair
Enveloppe 601372 | Niveau 1 | Enveloppe | 601372 | 366 | 9000 | 1977773087 | 1977773087 | 0 | 0 | 0976 | 04 | Niveau 1 | no | rectangle | 131.95 | 376.102 | 0.0128504 | 90.5267 | 376.102 | 270.527 | HAUT Niveau 1 (Niveau 2 13545) | 0 | <aucun> | Niveau 1 (Niveau 1 2343) | <aucun> | 131.9 | 131.9 | 376.1 | 376.1 | 1200 | 1200 | 1200 | 49600 | 450000 | Ivoire clair | Ivoire clair | 446639 | 211198 | 9 | 376.102 | 1187.55 | 49626.6 | 23466.5 | ...de stratigraphies = default; ...de matériaux et couleurs = Ivoire clair; ...de matériaux et couleurs - 1 = Ivoire clair; ...de matériaux et couleurs - 2 = Ivoire clair
Enveloppe 603705 | Niveau 1 | Enveloppe | 603705 | 366 | 9000 | 1977773087 | 1977773087 | 1 | 0 | 0979 | 04 | Niveau 1 | no | rectangle | 87.3836 | 376.102 | 0.0128504 | 90.7572 | 376.102 | 270.757 | HAUT Niveau 1 (Niveau 2 13545) | 0 | <aucun> | Niveau 1 (Niveau 1 2343) | <aucun> | 87.4 | 87.4 | 376.1 | 376.1 | 800 | 800 | 800 | 32900 | 300000 | Ivoire clair | Ivoire clair | 295787 | 295787 | 9 | 376.102 | 786.453 | 32865.2 | 32865.2 | ...de stratigraphies = default; ...de matériaux et couleurs = Ivoire clair; ...de matériaux et couleurs - 1 = Ivoire clair; ...de matériaux et couleurs - 2 = Ivoire clair
Enveloppe 603803 | Niveau 1 | Enveloppe | 603803 | 366 | 9000 | 1977773087 | 1977773087 | 1 | 0 | 0980 | 04 | Niveau 1 | yes | rectangle | 38.4466 | 376.102 | 0.0128504 | 5.23805 | 376.102 | 185.238 | HAUT Niveau 1 (Niveau 2 13545) | 0 | <aucun> | Niveau 1 (Niveau 1 2343) | <aucun> | 38.4 | 38.4 | 376.1 | 376.1 | 300 | 300 | 300 | 14400 | 130000 | Ivoire clair | Ivoire clair | 130139 | 130139 | 9 | 376.102 | 346.019 | 14459.9 | 14459.9 | ...de stratigraphies = default; ...de matériaux et couleurs = Ivoire clair; ...de matériaux et couleurs - 1 = Ivoire clair; ...de matériaux et couleurs - 2 = Ivoire clair
Enveloppe 601577 | Niveau 1 | Enveloppe | 601577 | 366 | 9000 | 1977773087 | 1977773087 | 1 | 0 | 0977 | 04 | Niveau 1 | yes | rectangle | 25.1582 | 376.102 | 0.0128504 | 174.098 | 376.102 | 354.098 | HAUT Niveau 1 (Niveau 2 13545) | 0 | <aucun> | Niveau 1 (Niveau 1 2343) | <aucun> | 25.2 | 25.2 | 376.1 | 376.1 | 200 | 200 | 200 | 9500 | 90000 | Ivoire clair | Ivoire clair | 85158.4 | 85158.4 | 9 | 376.102 | 226.424 | 9462.04 | 9462.04 | ...de stratigraphies = default; ...de matériaux et couleurs = Ivoire clair; ...de matériaux et couleurs - 1 = Ivoire clair; ...de matériaux et couleurs - 2 = Ivoire clair
Enveloppe 603704 | Niveau 1 | Enveloppe | 603704 | 366 | 9000 | 1977773087 | 1977773087 | 1 | 0 | 0978 | 04 | Niveau 1 | yes | rectangle | 38.7777 | 376.102 | 0.0128504 | 174.532 | 376.102 | 354.532 | HAUT Niveau 1 (Niveau 2 13545) | 0 | <aucun> | Niveau 1 (Niveau 1 2343) | <aucun> | 38.8 | 38.8 | 376.1 | 376.1 | 300 | 300 | 300 | 14600 | 130000 | Ivoire clair | Ivoire clair | 131259 | 131259 | 9 | 376.102 | 348.999 | 14584.4 | 14584.4 | ...de stratigraphies = default; ...de matériaux et couleurs = Ivoire clair; ...de matériaux et couleurs - 1 = Ivoire clair; ...de matériaux et couleurs - 2 = Ivoire clair
Enveloppe 600517 | Niveau 1 | Enveloppe | 600517 | 366 | 9000 | 1977773087 | 1977773087 | 0 | 0 | 0965 | 04 | Niveau 1 | yes | rectangle | 37.2033 | 376.102 | 0.0128504 | 94.7222 | 376.102 | 274.722 | HAUT Niveau 1 (Niveau 2 13545) | 0 | <aucun> | Niveau 1 (Niveau 1 2343) | <aucun> | 37.2 | 37.2 | 376.1 | 376.1 | 300 | 300 | 300 | 14000 | 130000 | Ivoire clair | Ivoire clair | 125930 | 125930 | 9 | 376.102 | 334.829 | 13992.2 | 13992.2 | ...de stratigraphies = default; ...de matériaux et couleurs = Ivoire clair; ...de matériaux et couleurs - 1 = Ivoire clair; ...de matériaux et couleurs - 2 = Ivoire clair
Enveloppe 600611 | Niveau 1 | Enveloppe | 600611 | 366 | 9000 | 1977773087 | 1977773087 | 1 | 0 | 0966 | 04 | Niveau 1 | yes | rectangle | 36.7585 | 376.102 | 0.0128504 | 0.120926 | 376.102 | 180.121 | HAUT Niveau 1 (Niveau 2 13545) | 0 | <aucun> | Niveau 1 (Niveau 1 2343) | <aucun> | 36.8 | 36.8 | 376.1 | 376.1 | 300 | 300 | 300 | 13800 | 120000 | Ivoire clair | Ivoire clair | 124425 | 124425 | 9 | 376.102 | 330.827 | 13825 | 13825 | ...de stratigraphies = default; ...de matériaux et couleurs = Ivoire clair; ...de matériaux et couleurs - 1 = Ivoire clair; ...de matériaux et couleurs - 2 = Ivoire clair
Enveloppe 599931 | Niveau 1 | Enveloppe | 599931 | 366 | 9000 | 1977773087 | 1977773087 | 1 | 0 | 0963 | 04 | Niveau 1 | yes | rectangle | 36.2194 | 376.102 | 0.0128504 | 83.973 | 376.102 | 263.973 | HAUT Niveau 1 (Niveau 2 13545) | 0 | <aucun> | Niveau 1 (Niveau 1 2343) | <aucun> | 36.2 | 36.2 | 376.1 | 376.1 | 300 | 300 | 300 | 13600 | 120000 | Ivoire clair | Ivoire clair | 122600 | 122600 | 9 | 376.102 | 325.974 | 13622.2 | 13622.2 | ...de stratigraphies = default; ...de matériaux et couleurs = Ivoire clair; ...de matériaux et couleurs - 1 = Ivoire clair; ...de matériaux et couleurs - 2 = Ivoire clair
Enveloppe 600231 | Niveau 1 | Enveloppe | 600231 | 366 | 9000 | 1977773087 | 1977773087 | 0 | 0 | 0964 | 04 | Niveau 1 | yes | rectangle | 42.6492 | 376.102 | 0.0128504 | 96.2123 | 376.102 | 276.212 | HAUT Niveau 1 (Niveau 2 13545) | 0 | <aucun> | Niveau 1 (Niveau 1 2343) | <aucun> | 42.6 | 42.6 | 376.1 | 376.1 | 400 | 400 | 400 | 16000 | 140000 | Ivoire clair | Ivoire clair | 144364 | 144364 | 9 | 376.102 | 383.843 | 16040.5 | 16040.5 | ...de stratigraphies = default; ...de matériaux et couleurs = Ivoire clair; ...de matériaux et couleurs - 1 = Ivoire clair; ...de matériaux et couleurs - 2 = Ivoire clair
Enveloppe 600644 | Niveau 1 | Enveloppe | 600644 | 366 | 9000 | 1977773087 | 1977773087 | 1 | 0 | 0967 | 04 | Niveau 1 | yes | rectangle | 37.8015 | 376.102 | 0.0128504 | 86.4233 | 376.102 | 266.423 | HAUT Niveau 1 (Niveau 2 13545) | 0 | <aucun> | Niveau 1 (Niveau 1 2343) | <aucun> | 37.8 | 37.8 | 376.1 | 376.1 | 300 | 300 | 300 | 14200 | 130000 | Ivoire clair | Ivoire clair | 127955 | 127955 | 9 | 376.102 | 340.214 | 14217.2 | 14217.2 | ...de stratigraphies = default; ...de matériaux et couleurs = Ivoire clair; ...de matériaux et couleurs - 1 = Ivoire clair; ...de matériaux et couleurs - 2 = Ivoire clair
Enveloppe 601010 | Niveau 1 | Enveloppe | 601010 | 366 | 9000 | 1977773087 | 1977773087 | 0 | 0 | 0970 | 04 | Niveau 1 | yes | rectangle | 183.025 | 376.102 | 0.0128504 | 179.995 | 376.102 | 359.995 | HAUT Niveau 1 (Niveau 2 13545) | 0 | <aucun> | Niveau 1 (Niveau 1 2343) | <aucun> | 183 | 183 | 376.1 | 376.1 | 1600 | 1600 | 1600 | 68800 | 620000 | Ivoire clair | Ivoire clair | 619525 | 619525 | 9 | 376.102 | 1647.22 | 68836.1 | 68836.1 | ...de stratigraphies = default; ...de matériaux et couleurs = Ivoire clair; ...de matériaux et couleurs - 1 = Ivoire clair; ...de matériaux et couleurs - 2 = Ivoire clair
Enveloppe 601044 | Niveau 1 | Enveloppe | 601044 | 366 | 9000 | 1977773087 | 1977773087 | 0 | 0 | 0971 | 04 | Niveau 1 | yes | rectangle | 36.3037 | 376.102 | 0.0128504 | 97.4294 | 376.102 | 277.429 | HAUT Niveau 1 (Niveau 2 13545) | 0 | <aucun> | Niveau 1 (Niveau 1 2343) | <aucun> | 36.3 | 36.3 | 376.1 | 376.1 | 300 | 300 | 300 | 13700 | 120000 | Ivoire clair | Ivoire clair | 122885 | 122885 | 9 | 376.102 | 326.733 | 13653.9 | 13653.9 | ...de stratigraphies = default; ...de matériaux et couleurs = Ivoire clair; ...de matériaux et couleurs - 1 = Ivoire clair; ...de matériaux et couleurs - 2 = Ivoire clair
Enveloppe 604055 | Niveau 1 | Enveloppe | 604055 | 366 | 9000 | 1977773087 | 1977773087 | 1 | 0 | 0983 | 04 | Niveau 1 | no | rectangle | 30.6458 | 376.102 | 0.0128504 | 173.22 | 376.102 | 353.22 | HAUT Niveau 1 (Niveau 2 13545) | 0 | <aucun> | Niveau 1 (Niveau 1 2343) | <aucun> | 30.6 | 30.6 | 376.1 | 376.1 | 300 | 300 | 300 | 11500 | 100000 | Ivoire clair | Ivoire clair | 103734 | 103734 | 9 | 376.102 | 275.812 | 11525.9 | 11525.9 | ...de stratigraphies = default; ...de matériaux et couleurs = Ivoire clair; ...de matériaux et couleurs - 1 = Ivoire clair; ...de matériaux et couleurs - 2 = Ivoire clair
Enveloppe 604739 | Niveau 1 | Enveloppe | 604739 | 366 | 9000 | 1977773087 | 1977773087 | 1 | 0 | 0984 | 04 | Niveau 1 | yes | rectangle | 35.7909 | 376.102 | 0.0128504 | 90.2476 | 376.102 | 270.248 | HAUT Niveau 1 (Niveau 2 13545) | 0 | <aucun> | Niveau 1 (Niveau 1 2343) | <aucun> | 35.8 | 35.8 | 376.1 | 376.1 | 300 | 300 | 300 | 13500 | 120000 | Ivoire clair | Ivoire clair | 121149 | 121149 | 9 | 376.102 | 322.118 | 13461 | 13461 | ...de stratigraphies = default; ...de matériaux et couleurs = Ivoire clair; ...de matériaux et couleurs - 1 = Ivoire clair; ...de matériaux et couleurs - 2 = Ivoire clair
Enveloppe 604054 | Niveau 1 | Enveloppe | 604054 | 366 | 9000 | 1977773087 | 1977773087 | 1 | 0 | 0982 | 04 | Niveau 1 | yes | rectangle | 29.7159 | 376.102 | 0.0128504 | 5.48295 | 376.102 | 185.483 | HAUT Niveau 1 (Niveau 2 13545) | 0 | <aucun> | Niveau 1 (Niveau 1 2343) | <aucun> | 29.7 | 29.7 | 376.1 | 376.1 | 300 | 300 | 300 | 11200 | 100000 | Ivoire clair | Ivoire clair | 100586 | 100586 | 9 | 376.102 | 267.443 | 11176.2 | 11176.2 | ...de stratigraphies = default; ...de matériaux et couleurs = Ivoire clair; ...de matériaux et couleurs - 1 = Ivoire clair; ...de matériaux et couleurs - 2 = Ivoire clair
Enveloppe 92637 | Niveau 1 | Enveloppe | 92637 | 366 | 9000 | 1977773087 | 1977773087 | 1 | 1 | 0188 | 04 | Niveau 1 | no | rectangle | 127.063 | 376.102 | 0.0128504 | 90.174 | 376.102 | 270.174 | HAUT Niveau 1 (Niveau 2 13545) | 0 | <aucun> | Niveau 1 (Niveau 1 2343) | <aucun> | 127.1 | 127.1 | 376.1 | 376.1 | 1100 | 1100 | 1100 | 47800 | 430000 | Ivoire clair | Ivoire clair | 430098 | 430098 | 9 | 376.102 | 1143.57 | 47788.7 | 47788.7 | ...de stratigraphies = default; ...de matériaux et couleurs = Ivoire clair; ...de matériaux et couleurs - 1 = Ivoire clair; ...de matériaux et couleurs - 2 = Ivoire clair
Enveloppe 92581 | Niveau 1 | Enveloppe | 92581 | 366 | 9000 | 1977773087 | 1977773087 | 1 | 1 | 0186 | 04 | Niveau 1 | no | rectangle | 90.599 | 376.102 | 0.0128504 | 1.07403 | 376.102 | 181.074 | HAUT Niveau 1 (Niveau 2 13545) | 0 | <aucun> | Niveau 1 (Niveau 1 2343) | <aucun> | 90.6 | 90.6 | 376.1 | 376.1 | 800 | 800 | 800 | 34100 | 310000 | Ivoire clair | Ivoire clair | 306670 | 306670 | 9 | 376.102 | 815.391 | 34074.5 | 34074.5 | ...de stratigraphies = default; ...de matériaux et couleurs = Ivoire clair; ...de matériaux et couleurs - 1 = Ivoire clair; ...de matériaux et couleurs - 2 = Ivoire clair
Enveloppe 92634 | Niveau 1 | Enveloppe | 92634 | 366 | 9000 | 1977773087 | 1977773087 | 0 | 1 | 0187 | 04 | Niveau 1 | no | rectangle | 126.435 | 376.102 | 0.0128504 | 0.905984 | 376.102 | 180.906 | HAUT Niveau 1 (Niveau 2 13545) | 0 | <aucun> | Niveau 1 (Niveau 1 2343) | <aucun> | 126.4 | 126.4 | 376.1 | 376.1 | 1100 | 1100 | 1100 | 47500 | 430000 | Ivoire clair | Ivoire clair | 427971 | 178690 | 9 | 376.102 | 1137.91 | 47552.4 | 19854.4 | ...de stratigraphies = default; ...de matériaux et couleurs = Ivoire clair; ...de matériaux et couleurs - 1 = Ivoire clair; ...de matériaux et couleurs - 2 = Ivoire clair
Enveloppe 92717 | Niveau 1 | Enveloppe | 92717 | 366 | 9000 | 1977773087 | 1977773087 | 0 | 1 | 0190 | 04 | Niveau 1 | no | rectangle | 235.759 | 376.102 | 0.0128504 | 0.649835 | 376.102 | 180.65 | HAUT Niveau 1 (Niveau 2 13545) | 0 | <aucun> | Niveau 1 (Niveau 1 2343) | <aucun> | 235.8 | 235.8 | 376.1 | 376.1 | 2100 | 2100 | 2100 | 88700 | 800000 | Ivoire clair | Ivoire clair | 798027 | 798027 | 9 | 376.102 | 2121.83 | 88669.6 | 88669.6 | ...de stratigraphies = default; ...de matériaux et couleurs = Ivoire clair; ...de matériaux et couleurs - 1 = Ivoire clair; ...de matériaux et couleurs - 2 = Ivoire clair
Enveloppe 93830 | Niveau 1 | Enveloppe | 93830 | 366 | 9000 | 1977773087 | 1977773087 | 0 | 0 | 0216 | 04 | Niveau 1 | no | rectangle | 133.783 | 376.102 | 0.0128504 | 0.505738 | 376.102 | 180.506 | HAUT Niveau 1 (Niveau 2 13545) | 0 | <aucun> | Niveau 1 (Niveau 1 2343) | <aucun> | 133.8 | 133.8 | 376.1 | 376.1 | 1200 | 1200 | 1200 | 50300 | 450000 | Ivoire clair | Ivoire clair | 452845 | 186531 | 9 | 376.102 | 1204.05 | 50316.1 | 20725.6 | ...de stratigraphies = default; ...de matériaux et couleurs = Ivoire clair; ...de matériaux et couleurs - 1 = Ivoire clair; ...de matériaux et couleurs - 2 = Ivoire clair
Enveloppe 93842 | Niveau 1 | Enveloppe | 93842 | 366 | 9000 | 1977773087 | 1977773087 | 0 | 0 | 0217 | 04 | Niveau 1 | no | rectangle | 150.81 | 376.102 | 0.0128504 | 90.4996 | 376.102 | 270.5 | HAUT Niveau 1 (Niveau 2 13545) | 0 | <aucun> | Niveau 1 (Niveau 1 2343) | <aucun> | 150.8 | 150.8 | 376.1 | 376.1 | 1400 | 1400 | 1400 | 56700 | 510000 | Ivoire clair | Ivoire clair | 510480 | 510480 | 9 | 376.102 | 1357.29 | 56720 | 56720 | ...de stratigraphies = default; ...de matériaux et couleurs = Ivoire clair; ...de matériaux et couleurs - 1 = Ivoire clair; ...de matériaux et couleurs - 2 = Ivoire clair
Enveloppe 93894 | Niveau 1 | Enveloppe | 93894 | 366 | 9000 | 1977773087 | 1977773087 | 1 | 0 | 0218 | 04 | Niveau 1 | no | rectangle | 190.171 | 376.102 | 0.0128504 | 90.2799 | 376.102 | 270.28 | HAUT Niveau 1 (Niveau 2 13545) | 0 | <aucun> | Niveau 1 (Niveau 1 2343) | <aucun> | 190.2 | 190.2 | 376.1 | 376.1 | 1700 | 1700 | 1700 | 71500 | 640000 | Ivoire clair | Ivoire clair | 643712 | 643712 | 9 | 376.102 | 1711.54 | 71523.6 | 71523.6 | ...de stratigraphies = default; ...de matériaux et couleurs = Ivoire clair; ...de matériaux et couleurs - 1 = Ivoire clair; ...de matériaux et couleurs - 2 = Ivoire clair
Enveloppe 93529 | Niveau 1 | Enveloppe | 93529 | 366 | 9000 | 1977773087 | 1977773087 | 0 | 0 | 0207 | 04 | Niveau 1 | no | rectangle | 202.944 | 376.102 | 0.0128504 | 90.4339 | 376.102 | 270.434 | HAUT Niveau 1 (Niveau 2 13545) | 0 | <aucun> | Niveau 1 (Niveau 1 2343) | <aucun> | 202.9 | 202.9 | 376.1 | 376.1 | 1800 | 1800 | 1800 | 76300 | 690000 | Ivoire clair | Ivoire clair | 686948 | 686948 | 9 | 376.102 | 1826.49 | 76327.6 | 76327.6 | ...de stratigraphies = default; ...de matériaux et couleurs = Ivoire clair; ...de matériaux et couleurs - 1 = Ivoire clair; ...de matériaux et couleurs - 2 = Ivoire clair
Enveloppe 93634 | Niveau 1 | Enveloppe | 93634 | 366 | 9000 | 1977773087 | 1977773087 | 0 | 0 | 0209 | 04 | Niveau 1 | no | rectangle | 110.776 | 376.102 | 0.0128504 | 89.5072 | 376.102 | 269.507 | HAUT Niveau 1 (Niveau 2 13545) | 0 | <aucun> | Niveau 1 (Niveau 1 2343) | <aucun> | 110.8 | 110.8 | 376.1 | 376.1 | 1000 | 1000 | 1000 | 41700 | 380000 | Ivoire clair | Ivoire clair | 374967 | 171267 | 9 | 376.102 | 996.981 | 41663 | 19029.7 | ...de stratigraphies = default; ...de matériaux et couleurs = Ivoire clair; ...de matériaux et couleurs - 1 = Ivoire clair; ...de matériaux et couleurs - 2 = Ivoire clair
Enveloppe 93682 | Niveau 1 | Enveloppe | 93682 | 366 | 9000 | 1977773087 | 1977773087 | 0 | 0 | 0210 | 04 | Niveau 1 | no | rectangle | 309.316 | 376.102 | 0.0128504 | 90.4339 | 376.102 | 270.434 | HAUT Niveau 1 (Niveau 2 13545) | 0 | <aucun> | Niveau 1 (Niveau 1 2343) | <aucun> | 309.3 | 309.3 | 376.1 | 376.1 | 2800 | 2800 | 2800 | 116300 | 1050000 | Ivoire clair | Ivoire clair | 1047010 | 1047010 | 9 | 376.102 | 2783.84 | 116334 | 116334 | ...de stratigraphies = default; ...de matériaux et couleurs = Ivoire clair; ...de matériaux et couleurs - 1 = Ivoire clair; ...de matériaux et couleurs - 2 = Ivoire clair
Enveloppe 104933 | Niveau 1 | Enveloppe | 104933 | 366 | 9000 | 1977773087 | 1977773087 | 1 | 0 | 0269 | 04 | Niveau 1 | no | rectangle | 128.257 | 376.102 | 0.0128504 | 0.187813 | 376.102 | 180.188 | HAUT Niveau 1 (Niveau 2 13545) | 0 | <aucun> | Niveau 1 (Niveau 1 2343) | <aucun> | 128.3 | 128.3 | 376.1 | 376.1 | 1200 | 1200 | 1200 | 48300 | 430000 | Ivoire clair | Ivoire clair | 434141 | 272427 | 9 | 376.102 | 1154.32 | 48237.8 | 30269.7 | ...de stratigraphies = default; ...de matériaux et couleurs = Ivoire clair; ...de matériaux et couleurs - 1 = Ivoire clair; ...de matériaux et couleurs - 2 = Ivoire clair
Enveloppe 106893 | Niveau 1 | Enveloppe | 106893 | 366 | 9000 | 1977773087 | 1977773087 | 1 | 0 | 0274 | 04 | Niveau 1 | no | rectangle | 125.194 | 232.487 | 0.0128504 | 0.064788 | 232.487 | 180.065 | HAUT Niveau 1 (Niveau 2 13545) | -143.615 | <aucun> | Niveau 1 (Niveau 1 2343) | <aucun> | 125.2 | 125.2 | 232.5 | 232.5 | 1100 | 1100 | 1100 | 29100 | 260000 | Ivoire clair | Ivoire clair | 261954 | 79042.9 | 9 | 232.487 | 1126.74 | 29105.9 | 8782.54 | ...de stratigraphies = default; ...de matériaux et couleurs = Ivoire clair; ...de matériaux et couleurs - 1 = Ivoire clair; ...de matériaux et couleurs - 2 = Ivoire clair
Enveloppe 119880 | Niveau 1 | Enveloppe | 119880 | 366 | 9000 | 1977773087 | 1977773087 | 1 | 0 | 0287 | 04 | Niveau 1 | no | rectangle | 127.059 | 376.102 | 0.0128504 | 90.174 | 376.102 | 270.174 | HAUT Niveau 1 (Niveau 2 13545) | 0 | <aucun> | Niveau 1 (Niveau 1 2343) | <aucun> | 127.1 | 127.1 | 376.1 | 376.1 | 1100 | 1100 | 1100 | 47800 | 430000 | Ivoire clair | Ivoire clair | 430084 | 232043 | 9 | 376.102 | 1143.53 | 47787.1 | 25782.6 | ...de stratigraphies = default; ...de matériaux et couleurs = Ivoire clair; ...de matériaux et couleurs - 1 = Ivoire clair; ...de matériaux et couleurs - 2 = Ivoire clair
Enveloppe 116176 | Niveau 1 | Enveloppe | 116176 | 366 | 9000 | 1977773087 | 1977773087 | 1 | 0 | 0280 | 04 | Niveau 1 | no | rectangle | 109.424 | 376.102 | 0.0128504 | 1.17378 | 376.102 | 181.174 | HAUT Niveau 1 (Niveau 2 13545) | 0 | <aucun> | Niveau 1 (Niveau 1 2343) | <aucun> | 109.4 | 109.4 | 376.1 | 376.1 | 1000 | 1000 | 1000 | 41100 | 370000 | Ivoire clair | Ivoire clair | 370391 | 370391 | 9 | 376.102 | 984.814 | 41154.5 | 41154.5 | ...de stratigraphies = default; ...de matériaux et couleurs = Ivoire clair; ...de matériaux et couleurs - 1 = Ivoire clair; ...de matériaux et couleurs - 2 = Ivoire clair
Enveloppe 111427 | Niveau 1 | Enveloppe | 111427 | 366 | 9000 | 1977773087 | 1977773087 | 1 | 0 | 0278 | 04 | Niveau 1 | no | rectangle | 127.976 | 235.487 | 0.0128504 | 0.243532 | 235.487 | 180.244 | HAUT Niveau 1 (Niveau 2 13545) | -140.615 | <aucun> | Niveau 1 (Niveau 1 2343) | <aucun> | 128 | 128 | 235.5 | 235.5 | 1200 | 1200 | 1200 | 30100 | 270000 | Ivoire clair | Ivoire clair | 271230 | 91565.8 | 9 | 235.487 | 1151.78 | 30136.7 | 10174 | ...de stratigraphies = default; ...de matériaux et couleurs = Ivoire clair; ...de matériaux et couleurs - 1 = Ivoire clair; ...de matériaux et couleurs - 2 = Ivoire clair
Enveloppe 94682 | Niveau 1 | Enveloppe | 94682 | 366 | 9000 | 1977773087 | 1977773087 | 1 | 0 | 0234 | 04 | Niveau 1 | no | rectangle | 197.197 | 376.102 | 0.0128504 | 179.894 | 376.102 | 359.894 | HAUT Niveau 1 (Niveau 2 13545) | 0 | <aucun> | Niveau 1 (Niveau 1 2343) | <aucun> | 197.2 | 197.2 | 376.1 | 376.1 | 1800 | 1800 | 1800 | 74200 | 670000 | Ivoire clair | Ivoire clair | 667497 | 667497 | 9 | 376.102 | 1774.78 | 74166.3 | 74166.3 | ...de stratigraphies = default; ...de matériaux et couleurs = Ivoire clair; ...de matériaux et couleurs - 1 = Ivoire clair; ...de matériaux et couleurs - 2 = Ivoire clair
Enveloppe 94660 | Niveau 1 | Enveloppe | 94660 | 366 | 9000 | 1977773087 | 1977773087 | 1 | 0 | 0232 | 04 | Niveau 1 | no | rectangle | 199.546 | 376.102 | 0.0128504 | 45.3123 | 376.102 | 225.312 | HAUT Niveau 1 (Niveau 2 13545) | 0 | <aucun> | Niveau 1 (Niveau 1 2343) | <aucun> | 199.5 | 199.5 | 376.1 | 376.1 | 1800 | 1800 | 1800 | 75000 | 680000 | Ivoire clair | Ivoire clair | 675447 | 675447 | 9 | 376.102 | 1795.91 | 75049.6 | 75049.6 | ...de stratigraphies = default; ...de matériaux et couleurs = Ivoire clair; ...de matériaux et couleurs - 1 = Ivoire clair; ...de matériaux et couleurs - 2 = Ivoire clair
Enveloppe 94750 | Niveau 1 | Enveloppe | 94750 | 366 | 9000 | 1977773087 | 1977773087 | 1 | 0 | 0238 | 04 | Niveau 1 | no | rectangle | 201.406 | 376.102 | 0.0128504 | 90.2083 | 376.102 | 270.208 | HAUT Niveau 1 (Niveau 2 13545) | 0 | <aucun> | Niveau 1 (Niveau 1 2343) | <aucun> | 201.4 | 201.4 | 376.1 | 376.1 | 1800 | 1800 | 1800 | 75700 | 680000 | Ivoire clair | Ivoire clair | 681744 | 681744 | 9 | 376.102 | 1812.66 | 75749.4 | 75749.4 | ...de stratigraphies = default; ...de matériaux et couleurs = Ivoire clair; ...de matériaux et couleurs - 1 = Ivoire clair; ...de matériaux et couleurs - 2 = Ivoire clair
Enveloppe 94314 | Niveau 1 | Enveloppe | 94314 | 366 | 9000 | 1977773087 | 1977773087 | 1 | 0 | 0224 | 04 | Niveau 1 | no | rectangle | 70.4921 | 376.102 | 0.0128504 | 90.7572 | 376.102 | 270.757 | HAUT Niveau 1 (Niveau 2 13545) | 0 | <aucun> | Niveau 1 (Niveau 1 2343) | <aucun> | 70.5 | 70.5 | 376.1 | 376.1 | 600 | 600 | 600 | 26500 | 240000 | Ivoire clair | Ivoire clair | 238610 | 238610 | 9 | 376.102 | 634.428 | 26512.2 | 26512.2 | ...de stratigraphies = default; ...de matériaux et couleurs = Ivoire clair; ...de matériaux et couleurs - 1 = Ivoire clair; ...de matériaux et couleurs - 2 = Ivoire clair
Enveloppe 94894 | Niveau 1 | Enveloppe | 94894 | 366 | 9000 | 1977773087 | 1977773087 | 0 | 0 | 0241 | 04 | Niveau 1 | no | rectangle | 214.323 | 376.102 | 0.0128504 | 179.965 | 376.102 | 359.965 | HAUT Niveau 1 (Niveau 2 13545) | 7.10543e-13 | <aucun> | Niveau 1 (Niveau 1 2343) | <aucun> | 214.3 | 214.3 | 376.1 | 376.1 | 1900 | 1900 | 1900 | 80600 | 730000 | Ivoire clair | Ivoire clair | 725468 | 725468 | 9 | 376.102 | 1928.91 | 80607.5 | 80607.5 | ...de stratigraphies = default; ...de matériaux et couleurs = Ivoire clair; ...de matériaux et couleurs - 1 = Ivoire clair; ...de matériaux et couleurs - 2 = Ivoire clair
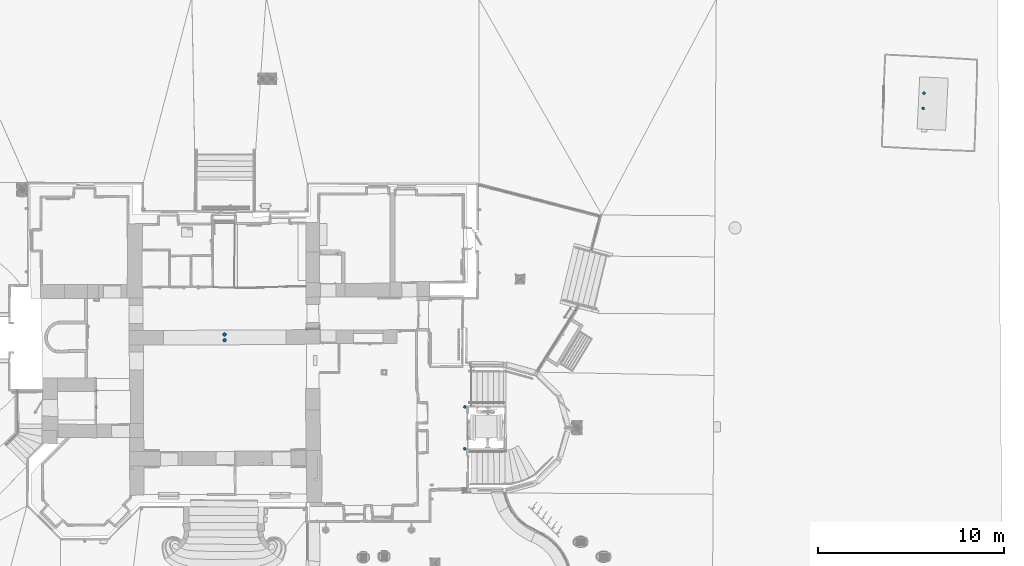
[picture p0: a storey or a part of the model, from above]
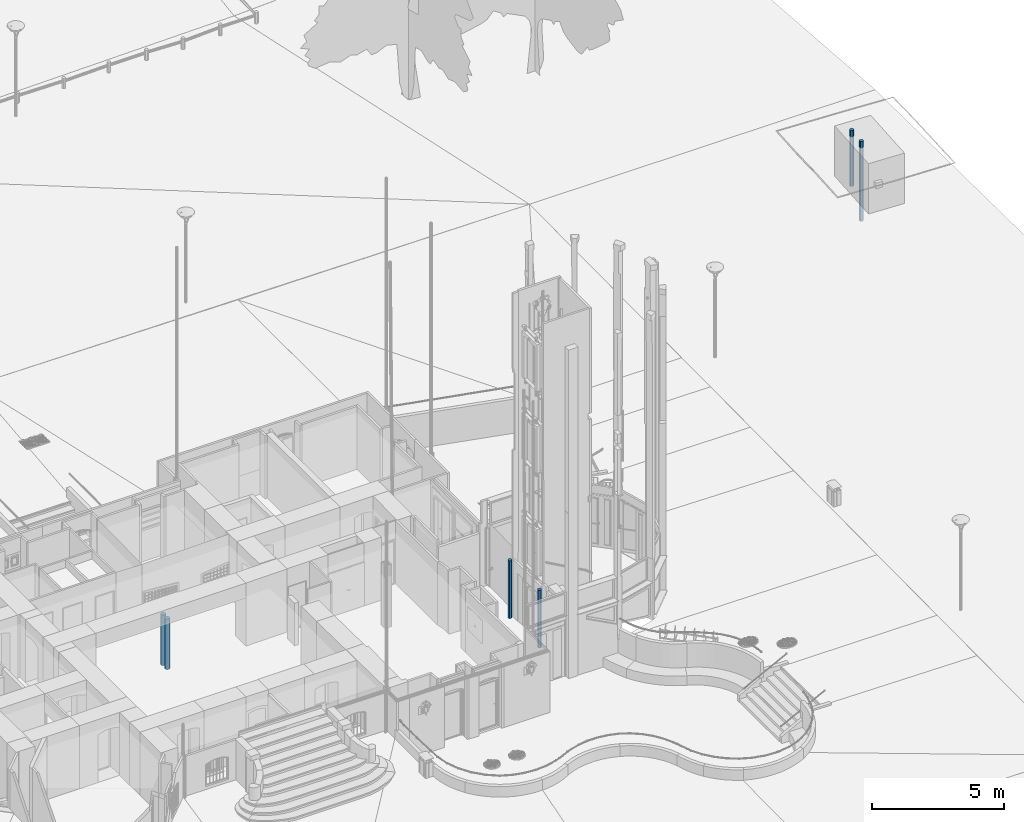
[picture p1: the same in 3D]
Properties of the parts of a building model (IFC2X3), part 33 of 37

# IfcWallStandardCase: default 90 (499)
Name | In | Description | __RECOGNIZE__, ID = IFC_Pset_Caractéristiques, ID | TPLG | TPLG_OD | 0, Crc | 1, Crc = 2, Crc | Alignment | ExternalFace | Numérotation | Numéro niveau | Titre niveau | Épaisseur VARIABLE | Forme en Élévation | Longueur (cm) = NominalLength (cm) | IFC_Pset_Géométrie, Hauteur (cm) = IFC_Pset_Géométrie_P1 (POINT initial), Hauteur (cm) | IFC_Pset_Géométrie, Cote (cm) = IFC_Pset_Géométrie_P1 (POINT initial), Cote (cm) = IFC_Pset_Géométrie_P2 (POINT final), Cote (cm) = IFC_Pset_Système de Référence Altimétrique_INFÉRIEUR, delta (cm) = IFC_Pset_Système de Référence Altimétrique_INFÉRIEUR, delta (P1) (cm) = IFC_Pset_Système de Référence Altimétrique_INFÉRIEUR, delta (P2) (cm) | IFC_Pset_Géométrie_P1 (POINT initial), Angle XY (deg) | IFC_Pset_Géométrie_P2 (POINT final), Hauteur (cm) | IFC_Pset_Géométrie_P2 (POINT final), Angle XY (deg) | IFC_Pset_Système de Référence Altimétrique_SUPÉRIEUR, NIVEAU | IFC_Pset_Système de Référence Altimétrique_SUPÉRIEUR, delta (cm) = IFC_Pset_Système de Référence Altimétrique_SUPÉRIEUR, delta (P1) (cm) = IFC_Pset_Système de Référence Altimétrique_SUPÉRIEUR, delta (P2) (cm) | IFC_Pset_Système de Référence Altimétrique_SUPÉRIEUR, sous Niveau | IFC_Pset_Système de Référence Altimétrique_INFÉRIEUR, NIVEAU | IFC_Pset_Système de Référence Altimétrique_INFÉRIEUR, sous Niveau | Longueur Pied (cm) | Longueur Tête (cm) | Hauteur Maximale (cm) | Hauteur Minimale (cm) | Surface en Plan (cm2) | Surface Pied (cm2) | Surface Tête (cm2) | Surface de la Paroi (cm2) | Volume (cm3) | Face gauche | Face droite = Face latérale | GrossVolume (cm3) | NetVolume (cm3) | NominalWidth (cm) | NominalHeight (cm) | GrossFootprintArea (cm2) = NetFootprintArea (cm2) | GrossSideArea (cm2) | NetSideArea (cm2) | Group
Enveloppe 597463 | Niveau 1 | Enveloppe | 597463 | 366 | 9000 | 1977773087 | 1977773087 | 0 | 1 | 0946 | 04 | Niveau 1 | no | rectangle | 283.23 | 376.102 | 0.0128504 | 0.0844895 | 376.102 | 180.084 | HAUT Niveau 1 (Niveau 2 13545) | 0 | <aucun> | Niveau 1 (Niveau 1 2343) | <aucun> | 283.2 | 283.2 | 376.1 | 376.1 | 2500 | 2500 | 2500 | 106500 | 960000 | Ivoire clair | Ivoire clair | 958710 | 457630 | 9 | 376.102 | 2549.07 | 106523 | 50847.8 | ...de stratigraphies = default; ...de matériaux et couleurs = Ivoire clair; ...de matériaux et couleurs - 1 = Ivoire clair; ...de matériaux et couleurs - 2 = Ivoire clair
Enveloppe 414209 | Niveau 1 | Enveloppe | 414209 | 366 | 9000 | 1908701706 | 1977773087 | 0 | 1 | 0671 | 04 | Niveau 1 | no | rectangle | 87.5325 | 659.115 | -295 | 89.9992 | 659.115 | 269.999 | HAUT Niveau 1 (Niveau 2 13545) | -12 | <aucun> | Niveau 1 (Niveau 1 2343) | <aucun> | 87.5 | 87.5 | 659.1 | 659.1 | 800 | 800 | 800 | 57700 | 520000 | Gris lumière | Ivoire clair | 519246 | 519246 | 9 | 659.115 | 787.792 | 57694 | 57694 | ...de stratigraphies = default; ...de matériaux et couleurs - 1 = Ivoire clair; ...de matériaux et couleurs - 2 = Ivoire clair; ...de matériaux et couleurs = Gris lumière
Enveloppe 775896 | Niveau 1 | Enveloppe | 775896 | 366 | 9000 | 1977773087 | 1977773087 | 1 | 0 | 1116 | 04 | Niveau 1 | no | rectangle | 266.586 | 376.102 | 0.0128504 | 0.257431 | 376.102 | 180.257 | HAUT Niveau 1 (Niveau 2 13545) | 0 | <aucun> | Niveau 1 (Niveau 1 2343) | <aucun> | 266.5 | 266.5 | 376.1 | 376.1 | 2300 | 2300 | 2300 | 100200 | 900000 | Ivoire clair | Ivoire clair | 902371 | 447121 | 9 | 376.102 | 2399.27 | 100263 | 49680.2 | ...de stratigraphies = default; ...de matériaux et couleurs = Ivoire clair; ...de matériaux et couleurs - 1 = Ivoire clair; ...de matériaux et couleurs - 2 = Ivoire clair
Enveloppe 93206 | Niveau 1 | Enveloppe | 93206 | 366 | 9000 | 1977773087 | 1977773087 | 0 | 0 | 0202 | 04 | Niveau 1 | no | rectangle | 196.82 | 376.102 | 0.0128504 | 91.1198 | 376.102 | 271.12 | HAUT Niveau 1 (Niveau 2 13545) | 0 | <aucun> | Niveau 1 (Niveau 1 2343) | <aucun> | 196.8 | 196.8 | 376.1 | 376.1 | 1700 | 1700 | 1700 | 74000 | 670000 | Ivoire clair | Ivoire clair | 666220 | 384244 | 9 | 376.102 | 1771.38 | 74024.4 | 42693.8 | ...de stratigraphies = default; ...de matériaux et couleurs = Ivoire clair; ...de matériaux et couleurs - 1 = Ivoire clair; ...de matériaux et couleurs - 2 = Ivoire clair
Enveloppe 599706 | Niveau 1 | Enveloppe | 599706 | 366 | 9000 | 1977773087 | 1977773087 | 0 | 1 | 0962 | 04 | Niveau 1 | no | rectangle | 185.991 | 376.102 | 0.0128504 | 0.905984 | 376.102 | 180.906 | HAUT Niveau 1 (Niveau 2 13545) | 0 | <aucun> | Niveau 1 (Niveau 1 2343) | <aucun> | 186 | 186 | 376.1 | 376.1 | 1700 | 1700 | 1700 | 70000 | 630000 | Ivoire clair | Ivoire clair | 629565 | 300183 | 9 | 376.102 | 1673.92 | 69951.7 | 33353.7 | ...de stratigraphies = default; ...de matériaux et couleurs = Ivoire clair; ...de matériaux et couleurs - 1 = Ivoire clair; ...de matériaux et couleurs - 2 = Ivoire clair
Enveloppe 93601 | Niveau 1 | Enveloppe | 93601 | 366 | 9000 | 1977773087 | 1977773087 | 0 | 0 | 0208 | 04 | Niveau 1 | no | rectangle | 103.418 | 376.102 | 0.0128504 | 90.154 | 376.102 | 270.154 | HAUT Niveau 1 (Niveau 2 13545) | 0 | <aucun> | Niveau 1 (Niveau 1 2343) | <aucun> | 103.4 | 103.4 | 376.1 | 376.1 | 1000 | 1000 | 1000 | 38900 | 350000 | Ivoire clair | Ivoire clair | 350063 | 350063 | 9 | 376.102 | 930.765 | 38895.9 | 38895.9 | ...de stratigraphies = default; ...de matériaux et couleurs = Ivoire clair; ...de matériaux et couleurs - 1 = Ivoire clair; ...de matériaux et couleurs - 2 = Ivoire clair
Enveloppe 464646 | Niveau 2 | Enveloppe | 464646 | 366 | 9000 | 1977773087 | 1977773087 | 1 | 1 | 0789 | 05 | Niveau 2 | no | trapèze | 98.9597 | 252.136 | -1.95399e-11 | 90.5085 | 255 | 270.509 | Couverture (Couverture 2134) | 0 | Toit783918 | Niveau 2 (Niveau 2 13545) | <aucun> | 99 | 99 | 255 | 252.1 | 900 | 900 | 900 | 25100 | 230000 | Ivoire clair | Ivoire clair | 225837 | 225837 | 9 | 253.568 | 890.637 | 25093 | 25093 | ...de stratigraphies = default; ...de matériaux et couleurs = Ivoire clair; ...de matériaux et couleurs - 1 = Ivoire clair; ...de matériaux et couleurs - 2 = Ivoire clair
Enveloppe 464904 | Niveau 2 | Enveloppe | 464904 | 366 | 9000 | 1977773087 | 1977773087 | 1 | 1 | 0790 | 05 | Niveau 2 | no | trapèze | 183.942 | 251.167 | -1.95399e-11 | 179.734 | 251.167 | 359.734 | Couverture (Couverture 2134) | 0 | Toit783918 | Niveau 2 (Niveau 2 13545) | <aucun> | 183.9 | 183.9 | 251.2 | 251.2 | 1700 | 1700 | 1700 | 46200 | 420000 | Ivoire clair | Ivoire clair | 415802 | 415802 | 9 | 251.167 | 1655.48 | 46200.2 | 46200.2 | ...de stratigraphies = default; ...de matériaux et couleurs = Ivoire clair; ...de matériaux et couleurs - 1 = Ivoire clair; ...de matériaux et couleurs - 2 = Ivoire clair
Enveloppe 464513 | Niveau 2 | Enveloppe | 464513 | 366 | 9000 | 1977773087 | 1977773087 | 0 | 1 | 0787 | 05 | Niveau 2 | no | rectangle | 47.1425 | 235 | -1.95399e-11 | 0.0196508 | 235 | 180.02 | HAUT Niveau 2 (Mezzanine 49003) | 8.34888e-12 | <aucun> | Niveau 2 (Niveau 2 13545) | <aucun> | 47.1 | 47.1 | 235 | 235 | 400 | 400 | 400 | 11100 | 100000 | Ivoire clair | Ivoire clair | 99706.4 | 99706.4 | 9 | 235 | 424.283 | 11078.5 | 11078.5 | ...de stratigraphies = default; ...de matériaux et couleurs = Ivoire clair; ...de matériaux et couleurs - 1 = Ivoire clair; ...de matériaux et couleurs - 2 = Ivoire clair
Enveloppe 464547 | Niveau 2 | Enveloppe | 464547 | 366 | 9000 | 1977773087 | 1977773087 | 1 | 1 | 0788 | 05 | Niveau 2 | no | rectangle | 75.1298 | 235 | -1.95399e-11 | 179.365 | 235 | 359.365 | HAUT Mezzanine (Couverture 2134) | -279.702 | <aucun> | Niveau 2 (Niveau 2 13545) | <aucun> | 75.1 | 75.1 | 235 | 235 | 700 | 700 | 700 | 17600 | 160000 | Ivoire clair | Ivoire clair | 158899 | 158899 | 9 | 235 | 676.168 | 17655.5 | 17655.5 | ...de stratigraphies = default; ...de matériaux et couleurs = Ivoire clair; ...de matériaux et couleurs - 1 = Ivoire clair; ...de matériaux et couleurs - 2 = Ivoire clair
Enveloppe 465079 | Niveau 2 | Enveloppe | 465079 | 366 | 9000 | 1977773087 | 1977773087 | 0 | 1 | 0791 | 05 | Niveau 2 | no | trapèze | 97.8067 | 254.385 | -1.95399e-11 | 0.585801 | 252.136 | 180.586 | Couverture (Couverture 2134) | 0 | Toit783918 | Niveau 2 (Niveau 2 13545) | <aucun> | 97.8 | 97.8 | 254.4 | 252.1 | 900 | 900 | 900 | 24800 | 220000 | Ivoire clair | Ivoire clair | 222935 | 222935 | 9 | 253.26 | 880.26 | 24770.5 | 24770.5 | ...de stratigraphies = default; ...de matériaux et couleurs = Ivoire clair; ...de matériaux et couleurs - 1 = Ivoire clair; ...de matériaux et couleurs - 2 = Ivoire clair
Enveloppe 465424 | Niveau 2 | Enveloppe | 465424 | 366 | 9000 | 1977773087 | 1977773087 | 0 | 1 | 0794 | 05 | Niveau 2 | no | rectangle | 32.12 | 235 | -1.95399e-11 | 88.5728 | 235 | 268.573 | Couverture (Couverture 2134) | -279.702 | <aucun> | Niveau 2 (Niveau 2 13545) | <aucun> | 32.1 | 32.1 | 235 | 235 | 300 | 300 | 300 | 7500 | 70000 | Ivoire clair | Ivoire clair | 67933.7 | 67933.7 | 9 | 235 | 289.08 | 7548.19 | 7548.19 | ...de stratigraphies = default; ...de matériaux et couleurs = Ivoire clair; ...de matériaux et couleurs - 1 = Ivoire clair; ...de matériaux et couleurs - 2 = Ivoire clair
Enveloppe 465458 | Niveau 2 | Enveloppe | 465458 | 366 | 9000 | 1977773087 | 1977773087 | 0 | 1 | 0795 | 05 | Niveau 2 | no | rectangle | 175.416 | 235 | -1.95399e-11 | 90.3734 | 235 | 270.373 | Couverture (Couverture 2134) | -279.702 | <aucun> | Niveau 2 (Niveau 2 13545) | <aucun> | 175.4 | 175.4 | 235 | 235 | 1600 | 1600 | 1600 | 41200 | 370000 | Ivoire clair | Ivoire clair | 371006 | 371006 | 9 | 235 | 1578.75 | 41222.9 | 41222.9 | ...de stratigraphies = default; ...de matériaux et couleurs = Ivoire clair; ...de matériaux et couleurs - 1 = Ivoire clair; ...de matériaux et couleurs - 2 = Ivoire clair
Enveloppe 465179 | Niveau 2 | Enveloppe | 465179 | 366 | 9000 | 1977773087 | 1977773087 | 1 | 1 | 0792 | 05 | Niveau 2 | no | trapèze | 81.0612 | 254.385 | -1.95399e-11 | 178.777 | 252.136 | 358.777 | Couverture (Couverture 2134) | 0 | Toit783918 | Niveau 2 (Niveau 2 13545) | <aucun> | 81.1 | 81.1 | 254.4 | 252.1 | 700 | 700 | 700 | 20500 | 180000 | Ivoire clair | Ivoire clair | 184766 | 184766 | 9 | 253.26 | 729.551 | 20529.6 | 20529.6 | ...de stratigraphies = default; ...de matériaux et couleurs = Ivoire clair; ...de matériaux et couleurs - 1 = Ivoire clair; ...de matériaux et couleurs - 2 = Ivoire clair
Enveloppe 465183 | Niveau 2 | Enveloppe | 465183 | 366 | 9000 | 1977773087 | 1977773087 | 0 | 1 | 0793 | 05 | Niveau 2 | no | trapèze | 149.349 | 252.866 | -1.95399e-11 | 90.1417 | 251.167 | 270.142 | Couverture (Couverture 2134) | 0 | Toit783918 | Niveau 2 (Niveau 2 13545) | <aucun> | 149.3 | 149.3 | 252.9 | 251.2 | 1300 | 1300 | 1300 | 37600 | 340000 | Ivoire clair | Ivoire clair | 338745 | 338745 | 9 | 252.017 | 1344.14 | 37638.3 | 37638.3 | ...de stratigraphies = default; ...de matériaux et couleurs = Ivoire clair; ...de matériaux et couleurs - 1 = Ivoire clair; ...de matériaux et couleurs - 2 = Ivoire clair
Enveloppe 463103 | Niveau 2 | Enveloppe | 463103 | 366 | 9000 | 1977773087 | 1977773087 | 1 | 1 | 0780 | 05 | Niveau 2 | no | trapèze | 212.382 | 279.31 | -1.95399e-11 | 0.130126 | 266.964 | 180.13 | Couverture (Couverture 2134) | 0 | Toit793924 | Niveau 2 (Niveau 2 13545) | <aucun> | 212.4 | 212.8 | 279.3 | 267 | 1900 | 1900 | 1900 | 58000 | 520000 | Ivoire clair | Ivoire clair | 522085 | 522085 | 9 | 273.137 | 1911.44 | 58009.4 | 58009.4 | ...de stratigraphies = default; ...de matériaux et couleurs = Ivoire clair; ...de matériaux et couleurs - 1 = Ivoire clair; ...de matériaux et couleurs - 2 = Ivoire clair
Enveloppe 463408 | Niveau 2 | Enveloppe | 463408 | 366 | 9000 | 1977773087 | 1977773087 | 1 | 1 | 0781 | 05 | Niveau 2 | no | rectangle | 178.609 | 235 | -1.95399e-11 | 89.4872 | 235 | 269.487 | HAUT Niveau 2 (Mezzanine 49003) | 1.61648e-11 | <aucun> | Niveau 2 (Niveau 2 13545) | <aucun> | 178.6 | 178.6 | 235 | 235 | 1600 | 1600 | 1600 | 42000 | 380000 | Ivoire clair | Ivoire clair | 377759 | 377759 | 9 | 235 | 1607.49 | 41973.2 | 41973.2 | ...de stratigraphies = default; ...de matériaux et couleurs = Ivoire clair; ...de matériaux et couleurs - 1 = Ivoire clair; ...de matériaux et couleurs - 2 = Ivoire clair
Enveloppe 462850 | Niveau 2 | Enveloppe | 462850 | 366 | 9000 | 1977773087 | 1977773087 | 1 | 1 | 0778 | 05 | Niveau 2 | no | rectangle | 105.965 | 254.622 | -1.95399e-11 | 89.9704 | 254.622 | 269.97 | Couverture (Couverture 2134) | -260.081 | <aucun> | Niveau 2 (Niveau 2 13545) | <aucun> | 106 | 106 | 254.6 | 254.6 | 1000 | 1000 | 1000 | 27000 | 240000 | Ivoire clair | Ivoire clair | 242828 | 242828 | 9 | 254.622 | 953.683 | 26980.9 | 26980.9 | ...de stratigraphies = default; ...de matériaux et couleurs = Ivoire clair; ...de matériaux et couleurs - 1 = Ivoire clair; ...de matériaux et couleurs - 2 = Ivoire clair
Enveloppe 462984 | Niveau 2 | Enveloppe | 462984 | 366 | 9000 | 1977773087 | 1977773087 | 1 | 1 | 0779 | 05 | Niveau 2 | no | rectangle | 329.446 | 245 | -1.95399e-11 | 89.6476 | 245 | 269.648 | HAUT Niveau 2 (Mezzanine 49003) | 10 | <aucun> | Niveau 2 (Niveau 2 13545) | <aucun> | 329.4 | 329.4 | 245 | 245 | 3000 | 3000 | 3000 | 80700 | 730000 | Ivoire clair | Ivoire clair | 726428 | 726428 | 9 | 245 | 2965.01 | 80714.3 | 80714.3 | ...de stratigraphies = default; ...de matériaux et couleurs = Ivoire clair; ...de matériaux et couleurs - 1 = Ivoire clair; ...de matériaux et couleurs - 2 = Ivoire clair
Enveloppe 463583 | Niveau 2 | Enveloppe | 463583 | 366 | 9000 | 1977773087 | 1977773087 | 1 | 1 | 0782 | 05 | Niveau 2 | no | rectangle | 182.625 | 235 | -1.95399e-11 | 90.2206 | 235 | 270.221 | HAUT Niveau 2 (Mezzanine 49003) | 1.61648e-11 | <aucun> | Niveau 2 (Niveau 2 13545) | <aucun> | 182.6 | 182.6 | 235 | 235 | 1600 | 1600 | 1600 | 42900 | 390000 | Ivoire clair | Ivoire clair | 386253 | 386253 | 9 | 235 | 1643.63 | 42917 | 42917 | ...de stratigraphies = default; ...de matériaux et couleurs = Ivoire clair; ...de matériaux et couleurs - 1 = Ivoire clair; ...de matériaux et couleurs - 2 = Ivoire clair
Enveloppe 464347 | Niveau 2 | Enveloppe | 464347 | 366 | 9000 | 1977773087 | 1977773087 | 1 | 1 | 0785 | 05 | Niveau 2 | no | rectangle | 75.6616 | 235 | -1.95399e-11 | 178.652 | 235 | 358.652 | HAUT Niveau 2 (Mezzanine 49003) | 7.99361e-12 | <aucun> | Niveau 2 (Niveau 2 13545) | <aucun> | 75.7 | 75.7 | 235 | 235 | 700 | 700 | 700 | 17800 | 160000 | Ivoire clair | Ivoire clair | 160024 | 160024 | 9 | 235 | 680.954 | 17780.5 | 17780.5 | ...de stratigraphies = default; ...de matériaux et couleurs = Ivoire clair; ...de matériaux et couleurs - 1 = Ivoire clair; ...de matériaux et couleurs - 2 = Ivoire clair
Enveloppe 464414 | Niveau 2 | Enveloppe | 464414 | 366 | 9000 | 1977773087 | 1977773087 | 1 | 1 | 0786 | 05 | Niveau 2 | no | rectangle | 67.4086 | 235 | -1.95399e-11 | 179.86 | 235 | 359.86 | HAUT Niveau 2 (Mezzanine 49003) | 7.99361e-12 | <aucun> | Niveau 2 (Niveau 2 13545) | <aucun> | 67.4 | 67.4 | 235 | 235 | 600 | 600 | 600 | 15800 | 140000 | Ivoire clair | Ivoire clair | 142569 | 142569 | 9 | 235 | 606.677 | 15841 | 15841 | ...de stratigraphies = default; ...de matériaux et couleurs = Ivoire clair; ...de matériaux et couleurs - 1 = Ivoire clair; ...de matériaux et couleurs - 2 = Ivoire clair
Enveloppe 463685 | Niveau 2 | Enveloppe | 463685 | 366 | 9000 | 1977773087 | 1977773087 | 1 | 1 | 0783 | 05 | Niveau 2 | no | trapèze | 258.446 | 261.398 | -1.95399e-11 | 179.806 | 261.398 | 359.806 | Couverture (Couverture 2134) | 0 | Toit793924 | Niveau 2 (Niveau 2 13545) | <aucun> | 258.4 | 258.4 | 261.4 | 261.4 | 2300 | 2300 | 2300 | 67500 | 610000 | Ivoire clair | Ivoire clair | 608014 | 608014 | 9 | 261.398 | 2326.01 | 67557.1 | 67557.1 | ...de stratigraphies = default; ...de matériaux et couleurs = Ivoire clair; ...de matériaux et couleurs - 1 = Ivoire clair; ...de matériaux et couleurs - 2 = Ivoire clair
Enveloppe 464007 | Niveau 2 | Enveloppe | 464007 | 366 | 9000 | 1977773087 | 1977773087 | 1 | 1 | 0784 | 05 | Niveau 2 | no | rectangle | 261.809 | 235 | -1.95399e-11 | 179.951 | 235 | 359.951 | HAUT Niveau 2 (Mezzanine 49003) | 7.63833e-12 | <aucun> | Niveau 2 (Niveau 2 13545) | <aucun> | 261.8 | 261.8 | 235 | 235 | 2400 | 2400 | 2400 | 61500 | 550000 | Ivoire clair | Ivoire clair | 553727 | 553727 | 9 | 235 | 2356.28 | 61525.2 | 61525.2 | ...de stratigraphies = default; ...de matériaux et couleurs = Ivoire clair; ...de matériaux et couleurs - 1 = Ivoire clair; ...de matériaux et couleurs - 2 = Ivoire clair
Enveloppe 466340 | Niveau 2 | Enveloppe | 466340 | 366 | 9000 | 1977773087 | 1977773087 | 1 | 1 | 0807 | 05 | Niveau 2 | no | trapèze | 195.516 | 260.728 | -1.95399e-11 | 89.3678 | 260.728 | 269.368 | Couverture (Couverture 2134) | 0 | Toit782750 | Niveau 2 (Niveau 2 13545) | <aucun> | 195.5 | 195.5 | 260.7 | 260.7 | 1800 | 1800 | 1800 | 50600 | 460000 | Ivoire clair | Ivoire clair | 455085 | 455085 | 9 | 258.624 | 1759.64 | 50565 | 50565 | ...de stratigraphies = default; ...de matériaux et couleurs = Ivoire clair; ...de matériaux et couleurs - 1 = Ivoire clair; ...de matériaux et couleurs - 2 = Ivoire clair
Enveloppe 466439 | Niveau 2 | Enveloppe | 466439 | 366 | 9000 | 1977773087 | 1977773087 | 1 | 1 | 0808 | 05 | Niveau 2 | no | rectangle | 70.2524 | 222 | -1.95399e-11 | 0.0864368 | 222 | 180.086 | HAUT Niveau 2 (Mezzanine 49003) | -13 | <aucun> | Niveau 2 (Niveau 2 13545) | <aucun> | 70.3 | 70.3 | 222 | 222 | 600 | 600 | 600 | 15600 | 140000 | Ivoire clair | Ivoire clair | 140364 | 140364 | 9 | 222 | 632.272 | 15596 | 15596 | ...de stratigraphies = default; ...de matériaux et couleurs = Ivoire clair; ...de matériaux et couleurs - 1 = Ivoire clair; ...de matériaux et couleurs - 2 = Ivoire clair
Enveloppe 466177 | Niveau 2 | Enveloppe | 466177 | 366 | 9000 | 1977773087 | 1977773087 | 1 | 1 | 0805 | 05 | Niveau 2 | no | rectangle | 23.3651 | 235 | -1.95399e-11 | 44.9617 | 235 | 224.962 | HAUT Niveau 2 (Mezzanine 49003) | 1.75859e-11 | <aucun> | Niveau 2 (Niveau 2 13545) | <aucun> | 23.4 | 23.4 | 235 | 235 | 200 | 200 | 200 | 5500 | 50000 | Ivoire clair | Ivoire clair | 49417.1 | 49417.1 | 9 | 235 | 210.286 | 5490.79 | 5490.79 | ...de stratigraphies = default; ...de matériaux et couleurs = Ivoire clair; ...de matériaux et couleurs - 1 = Ivoire clair; ...de matériaux et couleurs - 2 = Ivoire clair
Enveloppe 466257 | Niveau 2 | Enveloppe | 466257 | 366 | 9000 | 1977773087 | 1977773087 | 1 | 1 | 0806 | 05 | Niveau 2 | no | rectangle | 24.1576 | 235 | -1.95399e-11 | 43.9086 | 235 | 223.909 | HAUT Niveau 2 (Mezzanine 49003) | 1.75859e-11 | <aucun> | Niveau 2 (Niveau 2 13545) | <aucun> | 24.2 | 24.2 | 235 | 235 | 200 | 200 | 200 | 5700 | 50000 | Ivoire clair | Ivoire clair | 51093.4 | 51093.4 | 9 | 235 | 217.419 | 5677.05 | 5677.05 | ...de stratigraphies = default; ...de matériaux et couleurs = Ivoire clair; ...de matériaux et couleurs - 1 = Ivoire clair; ...de matériaux et couleurs - 2 = Ivoire clair
Enveloppe 466763 | Niveau 2 | Enveloppe | 466763 | 366 | 9000 | 1977773087 | 1977773087 | 1 | 1 | 0812 | 05 | Niveau 2 | no | rectangle | 56.9371 | 235 | -1.95399e-11 | 90.7599 | 235 | 270.76 | HAUT Niveau 2 (Mezzanine 49003) | 1.22569e-11 | <aucun> | Niveau 2 (Niveau 2 13545) | <aucun> | 56.9 | 56.9 | 235 | 235 | 500 | 500 | 500 | 13400 | 120000 | Ivoire clair | Ivoire clair | 120422 | 120422 | 9 | 235 | 512.434 | 13380.2 | 13380.2 | ...de stratigraphies = default; ...de matériaux et couleurs = Ivoire clair; ...de matériaux et couleurs - 1 = Ivoire clair; ...de matériaux et couleurs - 2 = Ivoire clair
Enveloppe 466764 | Niveau 2 | Enveloppe | 466764 | 366 | 9000 | 1977773087 | 1977773087 | 0 | 0 | 0813 | 05 | Niveau 2 | no | rectangle | 32.1598 | 240 | 1.42109e-12 | 0.759902 | 240 | 180.76 | HAUT Niveau 2 (Mezzanine 49003) | 5 | <aucun> | Niveau 2 (Niveau 2 13545) | <aucun> | 32.2 | 32.2 | 240 | 240 | 300 | 300 | 300 | 7700 | 70000 | Ivoire clair | Ivoire clair | 69465.1 | 69465.1 | 9 | 240 | 289.438 | 7718.35 | 7718.35 | ...de stratigraphies = default; ...de matériaux et couleurs = Ivoire clair; ...de matériaux et couleurs - 1 = Ivoire clair; ...de matériaux et couleurs - 2 = Ivoire clair
Enveloppe 466654 | Niveau 2 | Enveloppe | 466654 | 366 | 9000 | 1977773087 | 1977773087 | 0 | 1 | 0810 | 05 | Niveau 2 | no | rectangle | 56.9371 | 235 | -1.95399e-11 | 90.7599 | 235 | 270.76 | HAUT Niveau 2 (Mezzanine 49003) | 1.22569e-11 | <aucun> | Niveau 2 (Niveau 2 13545) | <aucun> | 56.9 | 56.9 | 235 | 235 | 500 | 500 | 500 | 13400 | 120000 | Ivoire clair | Ivoire clair | 120422 | 120422 | 9 | 235 | 512.434 | 13380.2 | 13380.2 | ...de stratigraphies = default; ...de matériaux et couleurs = Ivoire clair; ...de matériaux et couleurs - 1 = Ivoire clair; ...de matériaux et couleurs - 2 = Ivoire clair
Enveloppe 466655 | Niveau 2 | Enveloppe | 466655 | 366 | 9000 | 1977773087 | 1977773087 | 1 | 0 | 0811 | 05 | Niveau 2 | no | rectangle | 112.303 | 240 | 1.42109e-12 | 0.759902 | 240 | 180.76 | HAUT Niveau 2 (Mezzanine 49003) | 5 | <aucun> | Niveau 2 (Niveau 2 13545) | <aucun> | 112.3 | 112.3 | 240 | 240 | 1000 | 1000 | 1000 | 27000 | 240000 | Ivoire clair | Ivoire clair | 242574 | 97968.6 | 9 | 240 | 1010.72 | 26952.7 | 10885.4 | ...de stratigraphies = default; ...de matériaux et couleurs = Ivoire clair; ...de matériaux et couleurs - 1 = Ivoire clair; ...de matériaux et couleurs - 2 = Ivoire clair
Enveloppe 465666 | Niveau 2 | Enveloppe | 465666 | 366 | 9000 | 1977773087 | 1977773087 | 0 | 1 | 0799 | 05 | Niveau 2 | no | trapèze | 595.575 | 242.465 | -1.95399e-11 | 179.727 | 247.056 | 359.727 | Couverture (Couverture 2134) | 0 | Toit795367 | Niveau 2 (Niveau 2 13545) | <aucun> | 595.6 | 595.6 | 247.1 | 242.5 | 5400 | 5400 | 5400 | 145800 | 1310000 | Ivoire clair | Ivoire clair | 1311957 | 1215074 | 9 | 244.76 | 5360.18 | 145773 | 135008 | ...de stratigraphies = default; ...de matériaux et couleurs = Ivoire clair; ...de matériaux et couleurs - 1 = Ivoire clair; ...de matériaux et couleurs - 2 = Ivoire clair
Enveloppe 465557 | Niveau 2 | Enveloppe | 465557 | 366 | 9000 | 1977773087 | 1977773087 | 0 | 1 | 0796 | 05 | Niveau 2 | no | rectangle | 51.8878 | 235 | -1.95399e-11 | 0.41654 | 235 | 180.417 | HAUT Niveau 2 (Mezzanine 49003) | 1.5099e-11 | <aucun> | Niveau 2 (Niveau 2 13545) | <aucun> | 51.9 | 51.9 | 235 | 235 | 500 | 500 | 500 | 12200 | 110000 | Ivoire clair | Ivoire clair | 109743 | 109743 | 9 | 235 | 466.99 | 12193.6 | 12193.6 | ...de stratigraphies = default; ...de matériaux et couleurs = Ivoire clair; ...de matériaux et couleurs - 1 = Ivoire clair; ...de matériaux et couleurs - 2 = Ivoire clair
Enveloppe 465560 | Niveau 2 | Enveloppe | 465560 | 366 | 9000 | 1977773087 | 1977773087 | 0 | 1 | 0797 | 05 | Niveau 2 | no | rectangle | 95.7665 | 265.062 | -1.95399e-11 | 89.1206 | 265.062 | 269.121 | HAUT Mezzanine (Couverture 2134) | -249.641 | <aucun> | Niveau 2 (Niveau 2 13545) | <aucun> | 95.8 | 95.8 | 265.1 | 265.1 | 900 | 900 | 900 | 25400 | 230000 | Ivoire clair | Ivoire clair | 228456 | 228456 | 9 | 265.062 | 861.898 | 25384 | 25384 | ...de stratigraphies = default; ...de matériaux et couleurs = Ivoire clair; ...de matériaux et couleurs - 1 = Ivoire clair; ...de matériaux et couleurs - 2 = Ivoire clair
Enveloppe 465703 | Niveau 2 | Enveloppe | 465703 | 366 | 9000 | 1977773087 | 1977773087 | 0 | 1 | 0800 | 05 | Niveau 2 | no | trapèze | 190.252 | 259.037 | -1.95399e-11 | 44.6553 | 258.7 | 224.655 | Couverture (Couverture 2134) | 0 | Toit782750 | Niveau 2 (Niveau 2 13545) | <aucun> | 190.3 | 190.3 | 259 | 258.7 | 1700 | 1700 | 1700 | 49300 | 440000 | Ivoire clair | Ivoire clair | 443252 | 443252 | 9 | 258.868 | 1712.27 | 49250.2 | 49250.2 | ...de stratigraphies = default; ...de matériaux et couleurs = Ivoire clair; ...de matériaux et couleurs - 1 = Ivoire clair; ...de matériaux et couleurs - 2 = Ivoire clair
Enveloppe 465918 | Niveau 2 | Enveloppe | 465918 | 366 | 9000 | 1977773087 | 1977773087 | 0 | 1 | 0803 | 05 | Niveau 2 | no | rectangle | 24.473 | 235 | -1.95399e-11 | 134.119 | 235 | 314.119 | HAUT Niveau 2 (Mezzanine 49003) | 1.75859e-11 | <aucun> | Niveau 2 (Niveau 2 13545) | <aucun> | 24.5 | 24.5 | 235 | 235 | 200 | 200 | 200 | 5800 | 50000 | Ivoire clair | Ivoire clair | 51760.4 | 51760.4 | 9 | 235 | 220.257 | 5751.16 | 5751.16 | ...de stratigraphies = default; ...de matériaux et couleurs = Ivoire clair; ...de matériaux et couleurs - 1 = Ivoire clair; ...de matériaux et couleurs - 2 = Ivoire clair
Enveloppe 465969 | Niveau 2 | Enveloppe | 465969 | 366 | 9000 | 1977773087 | 1977773087 | 0 | 1 | 0804 | 05 | Niveau 2 | no | trapèze | 190.617 | 258.346 | -1.95399e-11 | 179.928 | 257.367 | 359.928 | Couverture (Couverture 2134) | 0 | Toit782750 | Niveau 2 (Niveau 2 13545) | <aucun> | 190.6 | 190.6 | 258.3 | 257.4 | 1700 | 1700 | 1700 | 49200 | 440000 | Ivoire clair | Ivoire clair | 442365 | 442365 | 9 | 257.856 | 1715.55 | 49151.6 | 49151.6 | ...de stratigraphies = default; ...de matériaux et couleurs = Ivoire clair; ...de matériaux et couleurs - 1 = Ivoire clair; ...de matériaux et couleurs - 2 = Ivoire clair
Enveloppe 465740 | Niveau 2 | Enveloppe | 465740 | 366 | 9000 | 1977773087 | 1977773087 | 0 | 1 | 0801 | 05 | Niveau 2 | no | trapèze | 191.713 | 258.237 | -1.95399e-11 | 89.4858 | 260.1 | 269.486 | Couverture (Couverture 2134) | 0 | Toit782750 | Niveau 2 (Niveau 2 13545) | <aucun> | 191.7 | 191.7 | 260.1 | 258.2 | 1700 | 1700 | 1700 | 49700 | 450000 | Ivoire clair | Ivoire clair | 447174 | 447174 | 9 | 259.168 | 1725.42 | 49686 | 49686 | ...de stratigraphies = default; ...de matériaux et couleurs = Ivoire clair; ...de matériaux et couleurs - 1 = Ivoire clair; ...de matériaux et couleurs - 2 = Ivoire clair
Enveloppe 465917 | Niveau 2 | Enveloppe | 465917 | 366 | 9000 | 1977773087 | 1977773087 | 0 | 1 | 0802 | 05 | Niveau 2 | no | rectangle | 22.5788 | 240 | -5 | 136.07 | 240 | 316.07 | HAUT Niveau 2 (Mezzanine 49003) | 1.65201e-11 | <aucun> | Niveau 2 (Niveau 2 13545) | <aucun> | 22.6 | 22.6 | 240 | 240 | 200 | 200 | 200 | 5400 | 50000 | Ivoire clair | Ivoire clair | 48770.3 | 48770.3 | 9 | 240 | 203.21 | 5418.92 | 5418.92 | ...de stratigraphies = default; ...de matériaux et couleurs = Ivoire clair; ...de matériaux et couleurs - 1 = Ivoire clair; ...de matériaux et couleurs - 2 = Ivoire clair
Enveloppe 462633 | Niveau 2 | Enveloppe | 462633 | 366 | 9000 | 1977773087 | 1977773087 | 1 | 1 | 0777 | 05 | Niveau 2 | no | rectangle | 106.247 | 254.622 | -1.95399e-11 | 89.9704 | 254.622 | 269.97 | Couverture (Couverture 2134) | -260.081 | <aucun> | Niveau 2 (Niveau 2 13545) | <aucun> | 106.2 | 106.2 | 254.6 | 254.6 | 1000 | 1000 | 1000 | 27000 | 240000 | Ivoire clair | Ivoire clair | 243476 | 243476 | 9 | 254.622 | 956.227 | 27052.9 | 27052.9 | ...de stratigraphies = default; ...de matériaux et couleurs = Ivoire clair; ...de matériaux et couleurs - 1 = Ivoire clair; ...de matériaux et couleurs - 2 = Ivoire clair
Enveloppe 461879 | Niveau 2 | Enveloppe | 461879 | 366 | 9000 | 1977773087 | 1977773087 | 0 | 1 | 0771 | 05 | Niveau 2 | no | rectangle | 106.305 | 245 | -1.95399e-11 | 89.7948 | 245 | 269.795 | Couverture (Couverture 2134) | -269.702 | <aucun> | Niveau 2 (Niveau 2 13545) | <aucun> | 106.3 | 106.3 | 245 | 245 | 1000 | 1000 | 1000 | 26000 | 230000 | Ivoire clair | Ivoire clair | 234402 | 234402 | 9 | 245 | 956.745 | 26044.7 | 26044.7 | ...de stratigraphies = default; ...de matériaux et couleurs = Ivoire clair; ...de matériaux et couleurs - 1 = Ivoire clair; ...de matériaux et couleurs - 2 = Ivoire clair
Enveloppe 462048 | Niveau 2 | Enveloppe | 462048 | 366 | 9000 | 1977773087 | 1977773087 | 0 | 1 | 0772 | 05 | Niveau 2 | no | rectangle | 91.9488 | 245 | -1.95399e-11 | 90.2773 | 245 | 270.277 | Couverture (Couverture 2134) | -269.702 | <aucun> | Niveau 2 (Niveau 2 13545) | <aucun> | 91.9 | 91.9 | 245 | 245 | 800 | 800 | 800 | 22500 | 200000 | Ivoire clair | Ivoire clair | 202747 | 202747 | 9 | 245 | 827.539 | 22527.5 | 22527.5 | ...de stratigraphies = default; ...de matériaux et couleurs = Ivoire clair; ...de matériaux et couleurs - 1 = Ivoire clair; ...de matériaux et couleurs - 2 = Ivoire clair
Enveloppe 462360 | Niveau 2 | Enveloppe | 462360 | 366 | 9000 | 1977773087 | 1977773087 | 1 | 1 | 0775 | 05 | Niveau 2 | no | rectangle | 133.596 | 255.509 | -1.95399e-11 | 0.0371683 | 255.509 | 180.037 | HAUT Niveau 2 (Mezzanine 49003) | 20.5086 | <aucun> | Niveau 2 (Niveau 2 13545) | <aucun> | 133.6 | 133.6 | 255.5 | 255.5 | 1200 | 1200 | 1200 | 34100 | 310000 | Ivoire clair | Ivoire clair | 307215 | 307215 | 9 | 255.509 | 1202.37 | 34135 | 34135 | ...de stratigraphies = default; ...de matériaux et couleurs = Ivoire clair; ...de matériaux et couleurs - 1 = Ivoire clair; ...de matériaux et couleurs - 2 = Ivoire clair
Enveloppe 462413 | Niveau 2 | Enveloppe | 462413 | 366 | 9000 | 1977773087 | 1977773087 | 1 | 1 | 0776 | 05 | Niveau 2 | no | trapèze | 196.364 | 255 | -1.95399e-11 | 89.4853 | 250.793 | 269.485 | Couverture (Couverture 2134) | 0 | Toit793923 | Niveau 2 (Niveau 2 13545) | <aucun> | 196.4 | 196.4 | 255 | 250.8 | 1800 | 1800 | 1800 | 49700 | 450000 | Ivoire clair | Ivoire clair | 446938 | 446938 | 9 | 252.897 | 1767.27 | 49659.7 | 49659.7 | ...de stratigraphies = default; ...de matériaux et couleurs = Ivoire clair; ...de matériaux et couleurs - 1 = Ivoire clair; ...de matériaux et couleurs - 2 = Ivoire clair
Enveloppe 462083 | Niveau 2 | Enveloppe | 462083 | 366 | 9000 | 1977773087 | 1977773087 | 0 | 1 | 0773 | 05 | Niveau 2 | no | rectangle | 64.348 | 245 | -1.95399e-11 | 88.3011 | 245 | 268.301 | Couverture (Couverture 2134) | -269.702 | <aucun> | Niveau 2 (Niveau 2 13545) | <aucun> | 64.3 | 64.3 | 245 | 245 | 600 | 600 | 600 | 15800 | 140000 | Ivoire clair | Ivoire clair | 141887 | 141887 | 9 | 245 | 579.132 | 15765.3 | 15765.3 | ...de stratigraphies = default; ...de matériaux et couleurs = Ivoire clair; ...de matériaux et couleurs - 1 = Ivoire clair; ...de matériaux et couleurs - 2 = Ivoire clair
Enveloppe 462309 | Niveau 2 | Enveloppe | 462309 | 366 | 9000 | 1977773087 | 1977773087 | 1 | 1 | 0774 | 05 | Niveau 2 | no | rectangle | 132.899 | 255.509 | -1.95399e-11 | 0.0371683 | 255.509 | 180.037 | HAUT Niveau 2 (Mezzanine 49003) | 20.5086 | <aucun> | Niveau 2 (Niveau 2 13545) | <aucun> | 132.9 | 132.9 | 255.5 | 255.5 | 1200 | 1200 | 1200 | 34000 | 310000 | Ivoire clair | Ivoire clair | 305612 | 305612 | 9 | 255.509 | 1196.09 | 33956.9 | 33956.9 | ...de stratigraphies = default; ...de matériaux et couleurs = Ivoire clair; ...de matériaux et couleurs - 1 = Ivoire clair; ...de matériaux et couleurs - 2 = Ivoire clair
Enveloppe 467083 | Niveau 2 | Enveloppe | 467083 | 366 | 9000 | 1977773087 | 1977773087 | 1 | 0 | 0814 | 05 | Niveau 2 | no | rectangle | 126.319 | 240 | 1.42109e-12 | 0.759902 | 240 | 180.76 | HAUT Niveau 2 (Mezzanine 49003) | 5 | <aucun> | Niveau 2 (Niveau 2 13545) | <aucun> | 126.3 | 126.3 | 240 | 240 | 1100 | 1100 | 1100 | 30300 | 270000 | Ivoire clair | Ivoire clair | 272850 | 129192 | 9 | 240 | 1136.87 | 30316.7 | 14354.6 | ...de stratigraphies = default; ...de matériaux et couleurs = Ivoire clair; ...de matériaux et couleurs - 1 = Ivoire clair; ...de matériaux et couleurs - 2 = Ivoire clair
Enveloppe 469112 | Niveau 2 | Enveloppe | 469112 | 366 | 9000 | 1977773087 | 1977773087 | 0 | 0 | 0826 | 05 | Niveau 2 | no | rectangle | 31.0057 | 235 | 1.42109e-12 | 89.6842 | 235 | 269.684 | HAUT Niveau 2 (Mezzanine 49003) | 0 | <aucun> | Niveau 2 (Niveau 2 13545) | <aucun> | 31 | 31 | 235 | 235 | 300 | 300 | 300 | 7300 | 70000 | Ivoire clair | Ivoire clair | 65577 | 65577 | 9 | 235 | 279.051 | 7286.33 | 7286.33 | ...de stratigraphies = default; ...de matériaux et couleurs = Ivoire clair; ...de matériaux et couleurs - 1 = Ivoire clair; ...de matériaux et couleurs - 2 = Ivoire clair
Enveloppe 469113 | Niveau 2 | Enveloppe | 469113 | 366 | 9000 | 1977773087 | 1977773087 | 1 | 0 | 0827 | 05 | Niveau 2 | no | rectangle | 106.309 | 235 | 1.42109e-12 | 179.684 | 235 | 359.684 | HAUT Niveau 2 (Mezzanine 49003) | 0 | <aucun> | Niveau 2 (Niveau 2 13545) | <aucun> | 106.3 | 106.3 | 235 | 235 | 1000 | 1000 | 1000 | 25000 | 230000 | Ivoire clair | Ivoire clair | 224844 | 224844 | 9 | 235 | 956.785 | 24982.7 | 24982.7 | ...de stratigraphies = default; ...de matériaux et couleurs = Ivoire clair; ...de matériaux et couleurs - 1 = Ivoire clair; ...de matériaux et couleurs - 2 = Ivoire clair
Enveloppe 468990 | Niveau 2 | Enveloppe | 468990 | 366 | 9000 | 1977773087 | 1977773087 | 0 | 0 | 0824 | 05 | Niveau 2 | no | rectangle | 37.6033 | 235 | 1.42109e-12 | 0.485897 | 235 | 180.486 | HAUT Niveau 2 (Mezzanine 49003) | 0 | <aucun> | Niveau 2 (Niveau 2 13545) | <aucun> | 37.6 | 37.6 | 235 | 235 | 300 | 300 | 300 | 8800 | 80000 | Ivoire clair | Ivoire clair | 79531 | 79531 | 9 | 235 | 338.43 | 8836.78 | 8836.78 | ...de stratigraphies = default; ...de matériaux et couleurs = Ivoire clair; ...de matériaux et couleurs - 1 = Ivoire clair; ...de matériaux et couleurs - 2 = Ivoire clair
Enveloppe 468995 | Niveau 2 | Enveloppe | 468995 | 366 | 9000 | 1977773087 | 1977773087 | 0 | 0 | 0825 | 05 | Niveau 2 | no | rectangle | 117.764 | 235 | 1.42109e-12 | 179.684 | 235 | 359.684 | HAUT Niveau 2 (Mezzanine 49003) | 0 | <aucun> | Niveau 2 (Niveau 2 13545) | <aucun> | 117.8 | 117.8 | 235 | 235 | 1100 | 1100 | 1100 | 27700 | 250000 | Ivoire clair | Ivoire clair | 249071 | 151183 | 9 | 235 | 1059.88 | 27674.6 | 16798.2 | ...de stratigraphies = default; ...de matériaux et couleurs = Ivoire clair; ...de matériaux et couleurs - 1 = Ivoire clair; ...de matériaux et couleurs - 2 = Ivoire clair
Enveloppe 470010 | Niveau 2 | Enveloppe | 470010 | 366 | 9000 | 1977773087 | 1977773087 | 0 | 0 | 0828 | 05 | Niveau 2 | no | rectangle | 39.5137 | 235 | 1.42109e-12 | 46.0382 | 235 | 226.038 | HAUT Niveau 2 (Mezzanine 49003) | 0 | <aucun> | Niveau 2 (Niveau 2 13545) | <aucun> | 39.5 | 39.5 | 235 | 235 | 400 | 400 | 400 | 9300 | 80000 | Ivoire clair | Ivoire clair | 83571.5 | 83571.5 | 9 | 235 | 355.624 | 9285.73 | 9285.73 | ...de stratigraphies = default; ...de matériaux et couleurs = Ivoire clair; ...de matériaux et couleurs - 1 = Ivoire clair; ...de matériaux et couleurs - 2 = Ivoire clair
Enveloppe 471715 | Niveau 2 | Enveloppe | 471715 | 366 | 9000 | 1977773087 | 1977773087 | 0 | 0 | 0832 | 05 | Niveau 2 | no | rectangle | 103.622 | 235 | 1.42109e-12 | 90.1119 | 235 | 270.112 | HAUT Niveau 2 (Mezzanine 49003) | 0 | <aucun> | Niveau 2 (Niveau 2 13545) | <aucun> | 103.6 | 103.6 | 235 | 235 | 900 | 900 | 900 | 24300 | 220000 | Ivoire clair | Ivoire clair | 219162 | 219162 | 9 | 235 | 932.602 | 24351.3 | 24351.3 | ...de stratigraphies = default; ...de matériaux et couleurs = Ivoire clair; ...de matériaux et couleurs - 1 = Ivoire clair; ...de matériaux et couleurs - 2 = Ivoire clair
Enveloppe 470107 | Niveau 2 | Enveloppe | 470107 | 366 | 9000 | 1977773087 | 1977773087 | 1 | 0 | 0829 | 05 | Niveau 2 | no | rectangle | 31.6637 | 235 | 1.42109e-12 | 45.1515 | 235 | 225.152 | HAUT Niveau 2 (Mezzanine 49003) | 0 | <aucun> | Niveau 2 (Niveau 2 13545) | <aucun> | 31.7 | 31.7 | 235 | 235 | 300 | 300 | 300 | 7400 | 70000 | Ivoire clair | Ivoire clair | 66968.7 | 66968.7 | 9 | 235 | 284.973 | 7440.97 | 7440.97 | ...de stratigraphies = default; ...de matériaux et couleurs = Ivoire clair; ...de matériaux et couleurs - 1 = Ivoire clair; ...de matériaux et couleurs - 2 = Ivoire clair
Enveloppe 467705 | Niveau 2 | Enveloppe | 467705 | 366 | 9000 | 1977773087 | 1977773087 | 1 | 0 | 0817 | 05 | Niveau 2 | no | rectangle | 116.315 | 235 | 1.42109e-12 | 1.07081 | 235 | 181.071 | HAUT Niveau 2 (Mezzanine 49003) | 0 | <aucun> | Niveau 2 (Niveau 2 13545) | <aucun> | 116.3 | 116.3 | 235 | 235 | 1000 | 1000 | 1000 | 27300 | 250000 | Ivoire clair | Ivoire clair | 246007 | 149423 | 9 | 235 | 1046.84 | 27334.1 | 16602.6 | ...de stratigraphies = default; ...de matériaux et couleurs = Ivoire clair; ...de matériaux et couleurs - 1 = Ivoire clair; ...de matériaux et couleurs - 2 = Ivoire clair
Enveloppe 467822 | Niveau 2 | Enveloppe | 467822 | 366 | 9000 | 1977773087 | 1977773087 | 1 | 1 | 0818 | 05 | Niveau 2 | no | rectangle | 36 | 235 | -1.95399e-11 | 91.0708 | 235 | 271.071 | HAUT Niveau 2 (Mezzanine 49003) | 1.29674e-11 | <aucun> | Niveau 2 (Niveau 2 13545) | <aucun> | 36 | 36 | 235 | 235 | 300 | 300 | 300 | 8500 | 80000 | Ivoire clair | Ivoire clair | 76140 | 76140 | 9 | 235 | 324 | 8460 | 8460 | ...de stratigraphies = default; ...de matériaux et couleurs = Ivoire clair; ...de matériaux et couleurs - 1 = Ivoire clair; ...de matériaux et couleurs - 2 = Ivoire clair
Enveloppe 467191 | Niveau 2 | Enveloppe | 467191 | 366 | 9000 | 1977773087 | 1977773087 | 1 | 1 | 0815 | 05 | Niveau 2 | no | rectangle | 44.1336 | 235 | -1.95399e-11 | 90.7599 | 235 | 270.76 | HAUT Niveau 2 (Mezzanine 49003) | 1.26121e-11 | <aucun> | Niveau 2 (Niveau 2 13545) | <aucun> | 44.1 | 44.1 | 235 | 235 | 400 | 400 | 400 | 10400 | 90000 | Ivoire clair | Ivoire clair | 93342.6 | 93342.6 | 9 | 235 | 397.203 | 10371.4 | 10371.4 | ...de stratigraphies = default; ...de matériaux et couleurs = Ivoire clair; ...de matériaux et couleurs - 1 = Ivoire clair; ...de matériaux et couleurs - 2 = Ivoire clair
Enveloppe 467505 | Niveau 2 | Enveloppe | 467505 | 366 | 9000 | 1977773087 | 1977773087 | 0 | 1 | 0816 | 05 | Niveau 2 | no | rectangle | 43.9321 | 235 | -1.95399e-11 | 90.7599 | 235 | 270.76 | HAUT Niveau 2 (Mezzanine 49003) | 1.22569e-11 | <aucun> | Niveau 2 (Niveau 2 13545) | <aucun> | 43.9 | 43.9 | 235 | 235 | 400 | 400 | 400 | 10300 | 90000 | Ivoire clair | Ivoire clair | 92916.3 | 92916.3 | 9 | 235 | 395.388 | 10324 | 10324 | ...de stratigraphies = default; ...de matériaux et couleurs = Ivoire clair; ...de matériaux et couleurs - 1 = Ivoire clair; ...de matériaux et couleurs - 2 = Ivoire clair
Enveloppe 467823 | Niveau 2 | Enveloppe | 467823 | 366 | 9000 | 1977773087 | 1977773087 | 0 | 0 | 0819 | 05 | Niveau 2 | no | rectangle | 107.609 | 235 | 1.42109e-12 | 1.07081 | 235 | 181.071 | HAUT Niveau 2 (Mezzanine 49003) | 0 | <aucun> | Niveau 2 (Niveau 2 13545) | <aucun> | 107.6 | 107.6 | 235 | 235 | 1000 | 1000 | 1000 | 25300 | 230000 | Ivoire clair | Ivoire clair | 227593 | 227593 | 9 | 235 | 968.482 | 25288.1 | 25288.1 | ...de stratigraphies = default; ...de matériaux et couleurs = Ivoire clair; ...de matériaux et couleurs - 1 = Ivoire clair; ...de matériaux et couleurs - 2 = Ivoire clair
Enveloppe 468778 | Niveau 2 | Enveloppe | 468778 | 366 | 9000 | 1977773087 | 1977773087 | 0 | 0 | 0822 | 05 | Niveau 2 | no | rectangle | 31 | 235 | 1.42109e-12 | 90.1357 | 235 | 270.136 | HAUT Niveau 2 (Mezzanine 49003) | 0 | <aucun> | Niveau 2 (Niveau 2 13545) | <aucun> | 31 | 31 | 235 | 235 | 300 | 300 | 300 | 7300 | 70000 | Ivoire clair | Ivoire clair | 65565 | 65565 | 9 | 235 | 279 | 7285 | 7285 | ...de stratigraphies = default; ...de matériaux et couleurs = Ivoire clair; ...de matériaux et couleurs - 1 = Ivoire clair; ...de matériaux et couleurs - 2 = Ivoire clair
Enveloppe 468852 | Niveau 2 | Enveloppe | 468852 | 366 | 9000 | 1977773087 | 1977773087 | 1 | 0 | 0823 | 05 | Niveau 2 | no | rectangle | 31 | 235 | 1.42109e-12 | 90.1357 | 235 | 270.136 | HAUT Niveau 2 (Mezzanine 49003) | 0 | <aucun> | Niveau 2 (Niveau 2 13545) | <aucun> | 31 | 31 | 235 | 235 | 300 | 300 | 300 | 7300 | 70000 | Ivoire clair | Ivoire clair | 65565 | 65565 | 9 | 235 | 279 | 7285 | 7285 | ...de stratigraphies = default; ...de matériaux et couleurs = Ivoire clair; ...de matériaux et couleurs - 1 = Ivoire clair; ...de matériaux et couleurs - 2 = Ivoire clair
Enveloppe 468287 | Niveau 2 | Enveloppe | 468287 | 366 | 9000 | 1977773087 | 1977773087 | 0 | 1 | 0820 | 05 | Niveau 2 | no | rectangle | 40 | 235 | -1.95399e-11 | 90.8495 | 235 | 270.85 | HAUT Niveau 2 (Mezzanine 49003) | 1.29674e-11 | <aucun> | Niveau 2 (Niveau 2 13545) | <aucun> | 40 | 40 | 235 | 235 | 400 | 400 | 400 | 9400 | 80000 | Ivoire clair | Ivoire clair | 84600 | 84600 | 9 | 235 | 360 | 9400 | 9400 | ...de stratigraphies = default; ...de matériaux et couleurs = Ivoire clair; ...de matériaux et couleurs - 1 = Ivoire clair; ...de matériaux et couleurs - 2 = Ivoire clair
Enveloppe 468325 | Niveau 2 | Enveloppe | 468325 | 366 | 9000 | 1977773087 | 1977773087 | 1 | 1 | 0821 | 05 | Niveau 2 | no | rectangle | 39.8429 | 235 | -1.95399e-11 | 90.8495 | 235 | 270.85 | HAUT Niveau 2 (Mezzanine 49003) | 1.33227e-11 | <aucun> | Niveau 2 (Niveau 2 13545) | <aucun> | 39.8 | 39.8 | 235 | 235 | 400 | 400 | 400 | 9400 | 80000 | Ivoire clair | Ivoire clair | 84267.7 | 84267.7 | 9 | 235 | 358.586 | 9363.08 | 9363.08 | ...de stratigraphies = default; ...de matériaux et couleurs = Ivoire clair; ...de matériaux et couleurs - 1 = Ivoire clair; ...de matériaux et couleurs - 2 = Ivoire clair
Enveloppe 749635 | Niveau 2 | Enveloppe | 749635 | 366 | 9000 | 1977773087 | 1977773087 | 0 | 0 | 1090 | 05 | Niveau 2 | no | rectangle | 74.7959 | 235 | 1.42109e-12 | 178.997 | 235 | 358.997 | HAUT Niveau 2 (Mezzanine 49003) | 1.43885e-11 | <aucun> | Niveau 2 (Niveau 2 13545) | <aucun> | 74.8 | 74.8 | 235 | 235 | 700 | 700 | 700 | 17600 | 160000 | Ivoire clair | Ivoire clair | 158193 | 158193 | 9 | 235 | 673.163 | 17577 | 17577 | ...de stratigraphies = default; ...de matériaux et couleurs = Ivoire clair; ...de matériaux et couleurs - 1 = Ivoire clair; ...de matériaux et couleurs - 2 = Ivoire clair
Enveloppe 748666 | Niveau 2 | Enveloppe | 748666 | 366 | 9000 | 1977773087 | 1977773087 | 0 | 0 | 1088 | 05 | Niveau 2 | no | rectangle | 88.8835 | 230 | 1.42109e-12 | 179.571 | 230 | 359.571 | HAUT Niveau 2 (Mezzanine 49003) | -5 | <aucun> | Niveau 2 (Niveau 2 13545) | <aucun> | 88.9 | 88.9 | 230 | 230 | 800 | 800 | 800 | 20400 | 180000 | Ivoire clair | Ivoire clair | 183989 | 183989 | 9 | 230 | 799.952 | 20443.2 | 20443.2 | ...de stratigraphies = default; ...de matériaux et couleurs = Ivoire clair; ...de matériaux et couleurs - 1 = Ivoire clair; ...de matériaux et couleurs - 2 = Ivoire clair
Enveloppe 734442 | Niveau 2 | Enveloppe | 734442 | 366 | 9000 | 1977773087 | 1977773087 | 1 | 0 | 1077 | 05 | Niveau 2 | no | rectangle | 24.2565 | 235 | 1.42109e-12 | 89.2229 | 235 | 269.223 | HAUT Niveau 2 (Mezzanine 49003) | 0 | <aucun> | Niveau 2 (Niveau 2 13545) | <aucun> | 24.3 | 24.3 | 235 | 235 | 200 | 200 | 200 | 5700 | 50000 | Ivoire clair | Ivoire clair | 51302.5 | 51302.5 | 9 | 235 | 218.308 | 5700.27 | 5700.27 | ...de stratigraphies = default; ...de matériaux et couleurs = Ivoire clair; ...de matériaux et couleurs - 1 = Ivoire clair; ...de matériaux et couleurs - 2 = Ivoire clair
Enveloppe 733954 | Niveau 2 | Enveloppe | 733954 | 366 | 9000 | 1977773087 | 1977773087 | 1 | 0 | 1074 | 05 | Niveau 2 | no | rectangle | 23.7561 | 235 | 8.52651e-12 | 90.5565 | 235 | 270.557 | HAUT Niveau 2 (Mezzanine 49003) | 1.40332e-11 | <aucun> | Niveau 2 (Niveau 2 13545) | <aucun> | 23.8 | 23.8 | 235 | 235 | 200 | 200 | 200 | 5600 | 50000 | Ivoire clair | Ivoire clair | 50244.1 | 50244.1 | 9 | 235 | 213.805 | 5582.67 | 5582.67 | ...de stratigraphies = default; ...de matériaux et couleurs = Ivoire clair; ...de matériaux et couleurs - 1 = Ivoire clair; ...de matériaux et couleurs - 2 = Ivoire clair
Enveloppe 734085 | Niveau 2 | Enveloppe | 734085 | 366 | 9000 | 1977773087 | 1977773087 | 1 | 0 | 1075 | 05 | Niveau 2 | no | rectangle | 53.5142 | 235 | 8.52651e-12 | 179.696 | 235 | 359.696 | HAUT Niveau 2 (Mezzanine 49003) | 1.40332e-11 | <aucun> | Niveau 2 (Niveau 2 13545) | <aucun> | 53.5 | 53.5 | 235 | 235 | 500 | 500 | 500 | 12600 | 110000 | Ivoire clair | Ivoire clair | 113182 | 113182 | 9 | 235 | 481.627 | 12575.8 | 12575.8 | ...de stratigraphies = default; ...de matériaux et couleurs = Ivoire clair; ...de matériaux et couleurs - 1 = Ivoire clair; ...de matériaux et couleurs - 2 = Ivoire clair
Enveloppe 739326 | Niveau 2 | Enveloppe | 739326 | 366 | 9000 | 1977773087 | 1977773087 | 0 | 1 | 1081 | 05 | Niveau 2 | no | rectangle | 35.0865 | 235 | -1.95399e-11 | 94.0789 | 235 | 274.079 | HAUT Niveau 2 (Mezzanine 49003) | 7.99361e-12 | <aucun> | Niveau 2 (Niveau 2 13545) | <aucun> | 35.1 | 35.1 | 235 | 235 | 300 | 300 | 300 | 8200 | 70000 | Ivoire clair | Ivoire clair | 74207.9 | 74207.9 | 9 | 235 | 315.778 | 8245.32 | 8245.32 | ...de stratigraphies = default; ...de matériaux et couleurs = Ivoire clair; ...de matériaux et couleurs - 1 = Ivoire clair; ...de matériaux et couleurs - 2 = Ivoire clair
Enveloppe 740170 | Niveau 2 | Enveloppe | 740170 | 366 | 9000 | 1977773087 | 1977773087 | 0 | 1 | 1082 | 05 | Niveau 2 | no | rectangle | 115.247 | 235 | -1.95399e-11 | 0.154484 | 235 | 180.154 | HAUT Niveau 2 (Mezzanine 49003) | 8.34888e-12 | <aucun> | Niveau 2 (Niveau 2 13545) | <aucun> | 115.2 | 115.2 | 235 | 235 | 1000 | 1000 | 1000 | 27100 | 240000 | Ivoire clair | Ivoire clair | 243746 | 243746 | 9 | 235 | 1037.22 | 27082.9 | 27082.9 | ...de stratigraphies = default; ...de matériaux et couleurs = Ivoire clair; ...de matériaux et couleurs - 1 = Ivoire clair; ...de matériaux et couleurs - 2 = Ivoire clair
Enveloppe 739246 | Niveau 2 | Enveloppe | 739246 | 366 | 9000 | 1977773087 | 1977773087 | 1 | 1 | 1080 | 05 | Niveau 2 | no | rectangle | 30.9224 | 235 | -1.95399e-11 | 89.6439 | 235 | 269.644 | HAUT Niveau 2 (Mezzanine 49003) | 7.99361e-12 | <aucun> | Niveau 2 (Niveau 2 13545) | <aucun> | 30.9 | 30.9 | 235 | 235 | 300 | 300 | 300 | 7300 | 70000 | Ivoire clair | Ivoire clair | 65400.9 | 65400.9 | 9 | 235 | 278.302 | 7266.77 | 7266.77 | ...de stratigraphies = default; ...de matériaux et couleurs = Ivoire clair; ...de matériaux et couleurs - 1 = Ivoire clair; ...de matériaux et couleurs - 2 = Ivoire clair
Enveloppe 733688 | Niveau 2 | Enveloppe | 733688 | 366 | 9000 | 1977773087 | 1977773087 | 1 | 0 | 1071 | 05 | Niveau 2 | no | trapèze | 21.5742 | 241.248 | 8.17124e-12 | 91.5432 | 272.927 | 271.543 | Couverture (Couverture 2134) | 0 | Toit793924 | Niveau 2 (Niveau 2 13545) | <aucun> | 21.6 | 38.4 | 272.9 | 241.2 | 200 | 200 | 300 | 5600 | 50000 | Ivoire clair | Ivoire clair | 49917.9 | 49917.9 | 9 | 257.087 | 194.167 | 5546.44 | 5546.44 | ...de stratigraphies = default; ...de matériaux et couleurs = Ivoire clair; ...de matériaux et couleurs - 1 = Ivoire clair; ...de matériaux et couleurs - 2 = Ivoire clair
Enveloppe 733843 | Niveau 2 | Enveloppe | 733843 | 366 | 9000 | 1977773087 | 1977773087 | 1 | 0 | 1072 | 05 | Niveau 2 | no | rectangle | 54.0242 | 235 | 8.52651e-12 | 0.394891 | 235 | 180.395 | HAUT Niveau 2 (Mezzanine 49003) | 1.40332e-11 | <aucun> | Niveau 2 (Niveau 2 13545) | <aucun> | 54 | 54 | 235 | 235 | 500 | 500 | 500 | 12700 | 110000 | Ivoire clair | Ivoire clair | 114261 | 114261 | 9 | 235 | 486.218 | 12695.7 | 12695.7 | ...de stratigraphies = default; ...de matériaux et couleurs = Ivoire clair; ...de matériaux et couleurs - 1 = Ivoire clair; ...de matériaux et couleurs - 2 = Ivoire clair
Enveloppe 1533952 | Niveau 2 | Enveloppe | 1533952 | 366 | 9000 | 1977773087 | 1977773087 | 0 | 1 | 1164 | 05 | Niveau 2 | no | rectangle | 209.136 | 349.702 | 1.13687e-11 | 89.3241 | 349.702 | 269.324 | HAUT Mezzanine (Couverture 2134) | -165 | <aucun> | Niveau 2 (Niveau 2 13545) | <aucun> | 209.1 | 209.1 | 349.7 | 349.7 | 1900 | 1900 | 1900 | 73100 | 660000 | Ivoire clair | Ivoire clair | 658217 | 490827 | 9 | 349.702 | 1882.22 | 73135.2 | 54536.4 | ...de stratigraphies = default; ...de matériaux et couleurs = Ivoire clair; ...de matériaux et couleurs - 1 = Ivoire clair; ...de matériaux et couleurs - 2 = Ivoire clair
Enveloppe 1528659 | Niveau 2 | Enveloppe | 1528659 | 366 | 9000 | 1977773087 | 1977773087 | 0 | 1 | 1163 | 05 | Niveau 2 | no | rectangle | 229.704 | 347.702 | 2 | 90.0265 | 347.702 | 270.027 | HAUT Mezzanine (Couverture 2134) | -165 | <aucun> | Niveau 2 (Niveau 2 13545) | <aucun> | 229.7 | 229.7 | 347.7 | 347.7 | 2100 | 2100 | 2100 | 79900 | 720000 | Ivoire clair | Ivoire clair | 718818 | 385828 | 9 | 347.702 | 2067.34 | 79868.7 | 42869.8 | ...de stratigraphies = default; ...de matériaux et couleurs = Ivoire clair; ...de matériaux et couleurs - 1 = Ivoire clair; ...de matériaux et couleurs - 2 = Ivoire clair
Enveloppe 177735 | Niveau 2 | Enveloppe | 177735 | 366 | 9000 | 1977773087 | 1977773087 | 0 | 0 | 0461 | 05 | Niveau 2 | no | rectangle | 28.4077 | 235 | 1.42109e-12 | 91.5181 | 235 | 271.518 | HAUT Niveau 2 (Mezzanine 49003) | 0 | <aucun> | Niveau 2 (Niveau 2 13545) | <aucun> | 28.4 | 28.4 | 235 | 235 | 300 | 300 | 300 | 6700 | 60000 | Ivoire clair | Ivoire clair | 60082.2 | 60082.2 | 9 | 235 | 255.669 | 6675.8 | 6675.8 | ...de stratigraphies = default; ...de matériaux et couleurs = Ivoire clair; ...de matériaux et couleurs - 1 = Ivoire clair; ...de matériaux et couleurs - 2 = Ivoire clair
Enveloppe 177736 | Niveau 2 | Enveloppe | 177736 | 366 | 9000 | 1977773087 | 1977773087 | 1 | 0 | 0462 | 05 | Niveau 2 | no | rectangle | 103.267 | 235 | 1.06581e-12 | 0.891614 | 235 | 180.892 | HAUT Niveau 2 (Mezzanine 49003) | 0 | <aucun> | Niveau 2 (Niveau 2 13545) | <aucun> | 103.3 | 103.3 | 235 | 235 | 900 | 900 | 900 | 24300 | 220000 | Ivoire clair | Ivoire clair | 218409 | 65268.3 | 9 | 235 | 929.399 | 24267.6 | 7252.03 | ...de stratigraphies = default; ...de matériaux et couleurs = Ivoire clair; ...de matériaux et couleurs - 1 = Ivoire clair; ...de matériaux et couleurs - 2 = Ivoire clair
Enveloppe 177689 | Niveau 2 | Enveloppe | 177689 | 366 | 9000 | 1977773087 | 1977773087 | 1 | 0 | 0459 | 05 | Niveau 2 | no | rectangle | 24.6071 | 235 | 1.42109e-12 | 90.8558 | 235 | 270.856 | HAUT Niveau 2 (Mezzanine 49003) | 0 | <aucun> | Niveau 2 (Niveau 2 13545) | <aucun> | 24.6 | 24.6 | 235 | 235 | 200 | 200 | 200 | 5800 | 50000 | Ivoire clair | Ivoire clair | 52044 | 52044 | 9 | 235 | 221.464 | 5782.67 | 5782.67 | ...de stratigraphies = default; ...de matériaux et couleurs = Ivoire clair; ...de matériaux et couleurs - 1 = Ivoire clair; ...de matériaux et couleurs - 2 = Ivoire clair
Enveloppe 177690 | Niveau 2 | Enveloppe | 177690 | 366 | 9000 | 1977773087 | 1977773087 | 1 | 0 | 0460 | 05 | Niveau 2 | no | rectangle | 277.059 | 235 | 1.06581e-12 | 0.558822 | 235 | 180.559 | HAUT Niveau 2 (Mezzanine 49003) | 0 | <aucun> | Niveau 2 (Niveau 2 13545) | <aucun> | 277.1 | 277.1 | 235 | 235 | 2500 | 2500 | 2500 | 65100 | 590000 | Ivoire clair | Ivoire clair | 585979 | 585979 | 9 | 235 | 2493.53 | 65108.8 | 65108.8 | ...de stratigraphies = default; ...de matériaux et couleurs = Ivoire clair; ...de matériaux et couleurs - 1 = Ivoire clair; ...de matériaux et couleurs - 2 = Ivoire clair
Enveloppe 178562 | Niveau 2 | Enveloppe | 178562 | 366 | 9000 | 1977773087 | 1977773087 | 1 | 0 | 0465 | 05 | Niveau 2 | yes | rectangle | 21.3953 | 235 | 1.42109e-12 | 0.558822 | 235 | 180.559 | HAUT Niveau 2 (Mezzanine 49003) | 0 | <aucun> | Niveau 2 (Niveau 2 13545) | <aucun> | 21.4 | 21.4 | 235 | 235 | 200 | 200 | 200 | 5000 | 50000 | Ivoire clair | Ivoire clair | 45251.1 | 45251.1 | 9 | 235 | 192.558 | 5027.91 | 5027.91 | ...de stratigraphies = default; ...de matériaux et couleurs = Ivoire clair; ...de matériaux et couleurs - 1 = Ivoire clair; ...de matériaux et couleurs - 2 = Ivoire clair
Enveloppe 177846 | Niveau 2 | Enveloppe | 177846 | 366 | 9000 | 1977773087 | 1977773087 | 1 | 0 | 0464 | 05 | Niveau 2 | no | rectangle | 118.481 | 235 | 1.06581e-12 | 0.696658 | 235 | 180.697 | HAUT Niveau 2 (Mezzanine 49003) | 0 | <aucun> | Niveau 2 (Niveau 2 13545) | <aucun> | 118.5 | 118.5 | 235 | 235 | 1100 | 1100 | 1100 | 27800 | 250000 | Ivoire clair | Ivoire clair | 250587 | 96300.9 | 9 | 235 | 1066.33 | 27843 | 10700.1 | ...de stratigraphies = default; ...de matériaux et couleurs = Ivoire clair; ...de matériaux et couleurs - 1 = Ivoire clair; ...de matériaux et couleurs - 2 = Ivoire clair
Enveloppe 151062 | Niveau 2 | Enveloppe | 151062 | 366 | 9000 | 1977773087 | 1977773087 | 1 | 0 | 0347 | 05 | Niveau 2 | yes | trapèze | 158.287 | 262.944 | 1.06581e-12 | 90.6789 | 259.997 | 270.679 | HAUT Niveau 2 (Mezzanine 49003) | 0 | <aucun> | Niveau 2 (Niveau 2 13545) | <aucun> | 158.3 | 158.3 | 262.9 | 260 | 1600 | 1600 | 1600 | 41400 | 410000 | Ivoire clair | Ivoire clair | 414359 | 414359 | 10.0117 | 261.471 | 1584.73 | 41387.5 | 41387.5 | ...de stratigraphies = default; ...de matériaux et couleurs = Ivoire clair; ...de matériaux et couleurs - 1 = Ivoire clair; ...de matériaux et couleurs - 2 = Ivoire clair
Enveloppe 150730 | Niveau 2 | Enveloppe | 150730 | 366 | 9000 | 1977773087 | 1977773087 | 0 | 0 | 0337 | 05 | Niveau 2 | no | rectangle | 135.175 | 240 | 1.42109e-12 | 0.759902 | 240 | 180.76 | HAUT Niveau 2 (Mezzanine 49003) | 5 | <aucun> | Niveau 2 (Niveau 2 13545) | <aucun> | 135.2 | 135.2 | 240 | 240 | 1200 | 1200 | 1200 | 32400 | 290000 | Ivoire clair | Ivoire clair | 291978 | 291978 | 9 | 240 | 1216.58 | 32442 | 32442 | ...de stratigraphies = default; ...de matériaux et couleurs = Ivoire clair; ...de matériaux et couleurs - 1 = Ivoire clair; ...de matériaux et couleurs - 2 = Ivoire clair
Enveloppe 150750 | Niveau 2 | Enveloppe | 150750 | 366 | 9000 | 1977773087 | 1977773087 | 1 | 0 | 0338 | 05 | Niveau 2 | no | rectangle | 135.832 | 240 | 1.42109e-12 | 179.609 | 240 | 359.609 | HAUT Niveau 2 (Mezzanine 49003) | 5 | <aucun> | Niveau 2 (Niveau 2 13545) | <aucun> | 135.8 | 135.8 | 240 | 240 | 1200 | 1200 | 1200 | 32600 | 290000 | Ivoire clair | Ivoire clair | 293397 | 293397 | 9 | 240 | 1222.49 | 32599.6 | 32599.6 | ...de stratigraphies = default; ...de matériaux et couleurs = Ivoire clair; ...de matériaux et couleurs - 1 = Ivoire clair; ...de matériaux et couleurs - 2 = Ivoire clair
Enveloppe 158783 | Niveau 2 | Enveloppe | 158783 | 366 | 9000 | 1977773087 | 1977773087 | 1 | 0 | 0363 | 05 | Niveau 2 | no | rectangle | 125.008 | 247.5 | 1.42109e-12 | 0.849549 | 247.5 | 180.85 | HAUT Niveau 2 (Mezzanine 49003) | 12.5 | <aucun> | Niveau 2 (Niveau 2 13545) | <aucun> | 125 | 125 | 247.5 | 247.5 | 1100 | 1100 | 1100 | 30900 | 280000 | Ivoire clair | Ivoire clair | 278455 | 157754 | 9 | 247.5 | 1125.07 | 30939.4 | 17528.3 | ...de stratigraphies = default; ...de matériaux et couleurs = Ivoire clair; ...de matériaux et couleurs - 1 = Ivoire clair; ...de matériaux et couleurs - 2 = Ivoire clair
Enveloppe 158791 | Niveau 2 | Enveloppe | 158791 | 366 | 9000 | 1977773087 | 1977773087 | 1 | 0 | 0364 | 05 | Niveau 2 | no | rectangle | 122.029 | 252.866 | 1.42109e-12 | 0.135735 | 252.866 | 180.136 | HAUT Niveau 2 (Mezzanine 49003) | 17.8665 | <aucun> | Niveau 2 (Niveau 2 13545) | <aucun> | 122 | 122 | 252.9 | 252.9 | 1100 | 1100 | 1100 | 30900 | 280000 | Ivoire clair | Ivoire clair | 277714 | 161655 | 9 | 252.866 | 1098.26 | 30857.1 | 17961.7 | ...de stratigraphies = default; ...de matériaux et couleurs = Ivoire clair; ...de matériaux et couleurs - 1 = Ivoire clair; ...de matériaux et couleurs - 2 = Ivoire clair
Enveloppe 159047 | Niveau 2 | Enveloppe | 159047 | 366 | 9000 | 1977773087 | 1977773087 | 1 | 0 | 0369 | 05 | Niveau 2 | no | rectangle | 56.1114 | 235 | 1.42109e-12 | 178.344 | 235 | 358.344 | HAUT Niveau 2 (Mezzanine 49003) | 0 | <aucun> | Niveau 2 (Niveau 2 13545) | <aucun> | 56.1 | 56.1 | 235 | 235 | 500 | 500 | 500 | 13200 | 120000 | Ivoire clair | Ivoire clair | 118676 | 118676 | 9 | 235 | 505.003 | 13186.2 | 13186.2 | ...de stratigraphies = default; ...de matériaux et couleurs = Ivoire clair; ...de matériaux et couleurs - 1 = Ivoire clair; ...de matériaux et couleurs - 2 = Ivoire clair
Enveloppe 153305 | Niveau 2 | Enveloppe | 153305 | 366 | 9000 | 1977773087 | 1977773087 | 0 | 0 | 0357 | 05 | Niveau 2 | yes | rectangle | 206.355 | 235 | 1.42109e-12 | 90.5207 | 235 | 270.521 | HAUT Niveau 2 (Mezzanine 49003) | 0 | <aucun> | Niveau 2 (Niveau 2 13545) | <aucun> | 206.4 | 206.4 | 235 | 235 | 2000 | 2000 | 2000 | 48500 | 490000 | Ivoire clair | Ivoire clair | 476828 | 476828 | 9.83282 | 235 | 2029.05 | 48493.5 | 48493.5 | ...de stratigraphies = default; ...de matériaux et couleurs = Ivoire clair; ...de matériaux et couleurs - 1 = Ivoire clair; ...de matériaux et couleurs - 2 = Ivoire clair
Enveloppe 150644 | Niveau 2 | Enveloppe | 150644 | 366 | 9000 | 1977773087 | 1977773087 | 0 | 0 | 0333 | 05 | Niveau 2 | yes | rectangle | 123.387 | 235 | 1.42109e-12 | 90.1355 | 235 | 270.136 | HAUT Niveau 2 (Mezzanine 49003) | 0 | <aucun> | Niveau 2 (Niveau 2 13545) | <aucun> | 123.4 | 123.4 | 235 | 235 | 1300 | 1300 | 1300 | 29000 | 290000 | Ivoire clair | Ivoire clair | 294033 | 294033 | 10.1405 | 235 | 1251.2 | 28996 | 28996 | ...de stratigraphies = default; ...de matériaux et couleurs = Ivoire clair; ...de matériaux et couleurs - 1 = Ivoire clair; ...de matériaux et couleurs - 2 = Ivoire clair
Enveloppe 150232 | Niveau 2 | Enveloppe | 150232 | 366 | 9000 | 1977773087 | 1977773087 | 0 | 0 | 0326 | 05 | Niveau 2 | no | rectangle | 107.335 | 235 | 1.42109e-12 | 90.8599 | 235 | 270.86 | HAUT Niveau 2 (Mezzanine 49003) | 0 | <aucun> | Niveau 2 (Niveau 2 13545) | <aucun> | 107.3 | 107.3 | 235 | 235 | 1000 | 1000 | 1000 | 25200 | 230000 | Ivoire clair | Ivoire clair | 227013 | 227013 | 9 | 235 | 966.011 | 25223.6 | 25223.6 | ...de stratigraphies = default; ...de matériaux et couleurs = Ivoire clair; ...de matériaux et couleurs - 1 = Ivoire clair; ...de matériaux et couleurs - 2 = Ivoire clair
Enveloppe 150253 | Niveau 2 | Enveloppe | 150253 | 366 | 9000 | 1977773087 | 1977773087 | 0 | 0 | 0327 | 05 | Niveau 2 | no | rectangle | 34.2264 | 235 | 1.42109e-12 | 90.8599 | 235 | 270.86 | HAUT Niveau 2 (Mezzanine 49003) | 0 | <aucun> | Niveau 2 (Niveau 2 13545) | <aucun> | 34.2 | 34.2 | 235 | 235 | 300 | 300 | 300 | 8000 | 70000 | Ivoire clair | Ivoire clair | 72388.9 | 72388.9 | 9 | 235 | 308.038 | 8043.21 | 8043.21 | ...de stratigraphies = default; ...de matériaux et couleurs = Ivoire clair; ...de matériaux et couleurs - 1 = Ivoire clair; ...de matériaux et couleurs - 2 = Ivoire clair
Enveloppe 150228 | Niveau 2 | Enveloppe | 150228 | 366 | 9000 | 1977773087 | 1977773087 | 0 | 0 | 0325 | 05 | Niveau 2 | no | rectangle | 421.577 | 235 | 1.42109e-12 | 89.7257 | 235 | 269.726 | HAUT Niveau 2 (Mezzanine 49003) | 0 | <aucun> | Niveau 2 (Niveau 2 13545) | <aucun> | 421.6 | 421.6 | 235 | 235 | 3800 | 3800 | 3800 | 99100 | 890000 | Ivoire clair | Ivoire clair | 891634 | 891634 | 9 | 235 | 3794.19 | 99070.5 | 99070.5 | ...de stratigraphies = default; ...de matériaux et couleurs = Ivoire clair; ...de matériaux et couleurs - 1 = Ivoire clair; ...de matériaux et couleurs - 2 = Ivoire clair
Enveloppe 149961 | Niveau 2 | Enveloppe | 149961 | 366 | 9000 | 1977773087 | 1977773087 | 1 | 0 | 0319 | 05 | Niveau 2 | no | rectangle | 241.945 | 235 | 1.06581e-12 | 0.590655 | 235 | 180.591 | HAUT Niveau 2 (Mezzanine 49003) | 0 | <aucun> | Niveau 2 (Niveau 2 13545) | <aucun> | 241.9 | 241.9 | 235 | 235 | 2200 | 2200 | 2200 | 56800 | 510000 | Ivoire clair | Ivoire clair | 511713 | 511713 | 9 | 235 | 2177.5 | 56857 | 56857 | ...de stratigraphies = default; ...de matériaux et couleurs = Ivoire clair; ...de matériaux et couleurs - 1 = Ivoire clair; ...de matériaux et couleurs - 2 = Ivoire clair
Enveloppe 150048 | Niveau 2 | Enveloppe | 150048 | 366 | 9000 | 1977773087 | 1977773087 | 0 | 0 | 0323 | 05 | Niveau 2 | no | rectangle | 251.327 | 235 | 1.42109e-12 | 0.51147 | 235 | 180.511 | HAUT Niveau 2 (Mezzanine 49003) | 0 | <aucun> | Niveau 2 (Niveau 2 13545) | <aucun> | 251.3 | 251.3 | 235 | 235 | 2300 | 2300 | 2300 | 59100 | 530000 | Ivoire clair | Ivoire clair | 531556 | 531556 | 9 | 235 | 2261.94 | 59061.8 | 59061.8 | ...de stratigraphies = default; ...de matériaux et couleurs = Ivoire clair; ...de matériaux et couleurs - 1 = Ivoire clair; ...de matériaux et couleurs - 2 = Ivoire clair
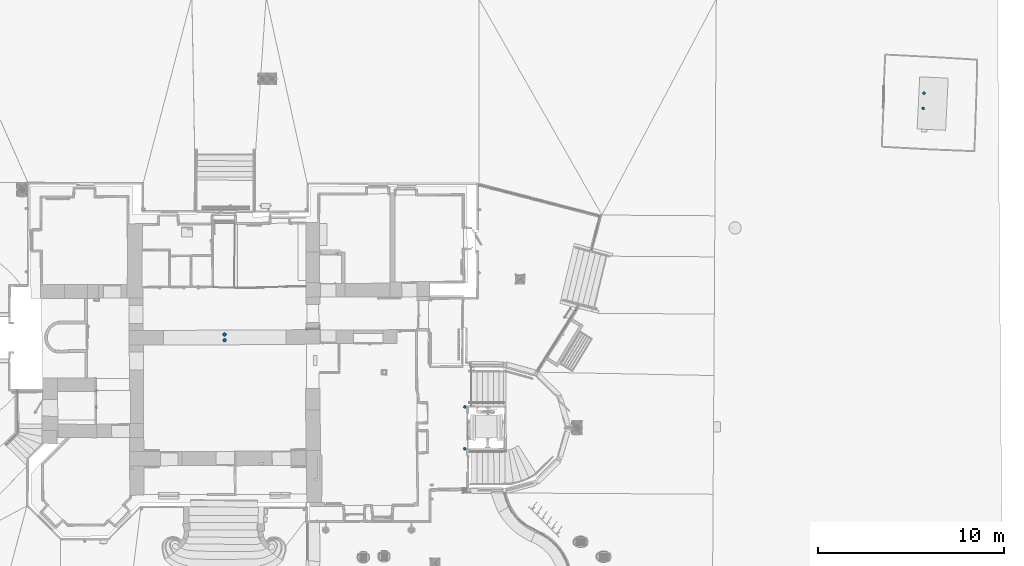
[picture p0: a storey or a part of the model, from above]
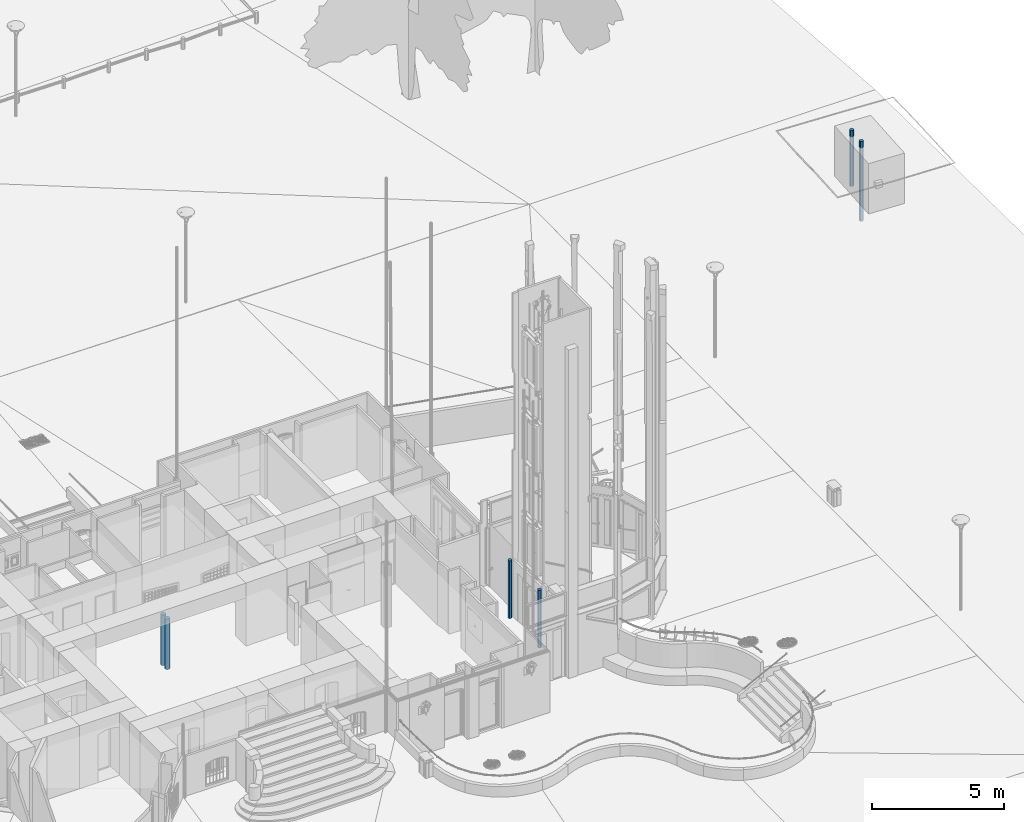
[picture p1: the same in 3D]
Properties of the parts of a building model (IFC2X3), part 34 of 37

# IfcWallStandardCase: default 90 (499)
Name | In | Description | __RECOGNIZE__, ID = IFC_Pset_Caractéristiques, ID | TPLG | TPLG_OD | 0, Crc | 1, Crc = 2, Crc | Alignment | ExternalFace | Numérotation | Numéro niveau | Titre niveau | Épaisseur VARIABLE | Forme en Élévation | Longueur (cm) = NominalLength (cm) | IFC_Pset_Géométrie, Hauteur (cm) = IFC_Pset_Géométrie_P1 (POINT initial), Hauteur (cm) | IFC_Pset_Géométrie, Cote (cm) = IFC_Pset_Géométrie_P1 (POINT initial), Cote (cm) = IFC_Pset_Géométrie_P2 (POINT final), Cote (cm) = IFC_Pset_Système de Référence Altimétrique_INFÉRIEUR, delta (cm) = IFC_Pset_Système de Référence Altimétrique_INFÉRIEUR, delta (P1) (cm) = IFC_Pset_Système de Référence Altimétrique_INFÉRIEUR, delta (P2) (cm) | IFC_Pset_Géométrie_P1 (POINT initial), Angle XY (deg) | IFC_Pset_Géométrie_P2 (POINT final), Hauteur (cm) | IFC_Pset_Géométrie_P2 (POINT final), Angle XY (deg) | IFC_Pset_Système de Référence Altimétrique_SUPÉRIEUR, NIVEAU | IFC_Pset_Système de Référence Altimétrique_SUPÉRIEUR, delta (cm) = IFC_Pset_Système de Référence Altimétrique_SUPÉRIEUR, delta (P1) (cm) = IFC_Pset_Système de Référence Altimétrique_SUPÉRIEUR, delta (P2) (cm) | IFC_Pset_Système de Référence Altimétrique_SUPÉRIEUR, sous Niveau | IFC_Pset_Système de Référence Altimétrique_INFÉRIEUR, NIVEAU | IFC_Pset_Système de Référence Altimétrique_INFÉRIEUR, sous Niveau | Longueur Pied (cm) | Longueur Tête (cm) | Hauteur Maximale (cm) | Hauteur Minimale (cm) | Surface en Plan (cm2) | Surface Pied (cm2) | Surface Tête (cm2) | Surface de la Paroi (cm2) | Volume (cm3) | Face gauche | Face droite = Face latérale | GrossVolume (cm3) | NetVolume (cm3) | NominalWidth (cm) | NominalHeight (cm) | GrossFootprintArea (cm2) = NetFootprintArea (cm2) | GrossSideArea (cm2) | NetSideArea (cm2) | Group
Enveloppe 150023 | Niveau 2 | Enveloppe | 150023 | 366 | 9000 | 1977773087 | 1977773087 | 0 | 0 | 0320 | 05 | Niveau 2 | no | rectangle | 180.218 | 235 | 1.42109e-12 | 91.0452 | 235 | 271.045 | HAUT Niveau 2 (Mezzanine 49003) | 0 | <aucun> | Niveau 2 (Niveau 2 13545) | <aucun> | 180.2 | 180.2 | 235 | 235 | 1600 | 1600 | 1600 | 42300 | 380000 | Ivoire clair | Ivoire clair | 381161 | 381161 | 9 | 235 | 1621.96 | 42351.2 | 42351.2 | ...de stratigraphies = default; ...de matériaux et couleurs = Ivoire clair; ...de matériaux et couleurs - 1 = Ivoire clair; ...de matériaux et couleurs - 2 = Ivoire clair
Enveloppe 159068 | Niveau 2 | Enveloppe | 159068 | 366 | 9000 | 1977773087 | 1977773087 | 0 | 0 | 0370 | 05 | Niveau 2 | yes | rectangle | 58.2943 | 235 | 1.42109e-12 | 47.5434 | 235 | 227.543 | HAUT Niveau 2 (Mezzanine 49003) | 0 | <aucun> | Niveau 2 (Niveau 2 13545) | <aucun> | 58.3 | 58.3 | 235 | 235 | 500 | 500 | 500 | 13700 | 120000 | Ivoire clair | Ivoire clair | 123292 | 123292 | 9 | 235 | 524.648 | 13699.2 | 13699.2 | ...de stratigraphies = default; ...de matériaux et couleurs = Ivoire clair; ...de matériaux et couleurs - 1 = Ivoire clair; ...de matériaux et couleurs - 2 = Ivoire clair
Enveloppe 170792 | Niveau 2 | Enveloppe | 170792 | 366 | 9000 | 1977773087 | 1977773087 | 1 | 0 | 0425 | 05 | Niveau 2 | no | rectangle | 20 | 235 | 1.42109e-12 | 1.07416 | 235 | 181.074 | HAUT Niveau 2 (Mezzanine 49003) | 1.42109e-12 | <aucun> | Niveau 2 (Niveau 2 13545) | <aucun> | 20 | 20 | 235 | 235 | 200 | 200 | 200 | 4700 | 40000 | Ivoire clair | Ivoire clair | 42300 | 42300 | 9 | 235 | 180 | 4700 | 4700 | ...de stratigraphies = default; ...de matériaux et couleurs = Ivoire clair; ...de matériaux et couleurs - 1 = Ivoire clair; ...de matériaux et couleurs - 2 = Ivoire clair
Enveloppe 172730 | Niveau 2 | Enveloppe | 172730 | 366 | 9000 | 1977773087 | 1977773087 | 1 | 0 | 0438 | 05 | Niveau 2 | no | rectangle | 42.1642 | 235 | 1.42109e-12 | 89.7204 | 235 | 269.72 | HAUT Niveau 2 (Mezzanine 49003) | 1.42109e-12 | <aucun> | Niveau 2 (Niveau 2 13545) | <aucun> | 42.2 | 42.2 | 235 | 235 | 400 | 400 | 400 | 9900 | 90000 | Ivoire clair | Ivoire clair | 89177.3 | 89177.3 | 9 | 235 | 379.478 | 9908.59 | 9908.59 | ...de stratigraphies = default; ...de matériaux et couleurs = Ivoire clair; ...de matériaux et couleurs - 1 = Ivoire clair; ...de matériaux et couleurs - 2 = Ivoire clair
Enveloppe 175458 | Niveau 2 | Enveloppe | 175458 | 366 | 9000 | 1977773087 | 1977773087 | 1 | 0 | 0443 | 05 | Niveau 2 | no | rectangle | 100.672 | 225 | 1.42109e-12 | 90.0751 | 225 | 270.075 | HAUT Niveau 2 (Mezzanine 49003) | -10 | <aucun> | Niveau 2 (Niveau 2 13545) | <aucun> | 100.7 | 100.7 | 225 | 225 | 900 | 900 | 900 | 22700 | 200000 | Ivoire clair | Ivoire clair | 203860 | 203860 | 9 | 225 | 906.045 | 22651.1 | 22651.1 | ...de stratigraphies = default; ...de matériaux et couleurs = Ivoire clair; ...de matériaux et couleurs - 1 = Ivoire clair; ...de matériaux et couleurs - 2 = Ivoire clair
Enveloppe 172842 | Niveau 2 | Enveloppe | 172842 | 366 | 9000 | 1977773087 | 1977773087 | 0 | 0 | 0440 | 05 | Niveau 2 | no | rectangle | 40.2295 | 235 | 1.42109e-12 | 89.9261 | 235 | 269.926 | HAUT Niveau 2 (Mezzanine 49003) | 1.42109e-12 | <aucun> | Niveau 2 (Niveau 2 13545) | <aucun> | 40.2 | 40.2 | 235 | 235 | 400 | 400 | 400 | 9400 | 80000 | Ivoire clair | Ivoire clair | 85085.4 | 85085.4 | 9 | 235 | 362.065 | 9453.93 | 9453.93 | ...de stratigraphies = default; ...de matériaux et couleurs = Ivoire clair; ...de matériaux et couleurs - 1 = Ivoire clair; ...de matériaux et couleurs - 2 = Ivoire clair
Enveloppe 170929 | Niveau 2 | Enveloppe | 170929 | 366 | 9000 | 1977773087 | 1977773087 | 1 | 0 | 0428 | 05 | Niveau 2 | no | rectangle | 28.0659 | 235 | 1.42109e-12 | 177.126 | 235 | 357.126 | HAUT Niveau 2 (Mezzanine 49003) | 1.42109e-12 | <aucun> | Niveau 2 (Niveau 2 13545) | <aucun> | 28.1 | 28.1 | 235 | 235 | 300 | 300 | 300 | 6600 | 60000 | Ivoire clair | Ivoire clair | 59359.5 | 59359.5 | 9 | 235 | 252.593 | 6595.5 | 6595.5 | ...de stratigraphies = default; ...de matériaux et couleurs = Ivoire clair; ...de matériaux et couleurs - 1 = Ivoire clair; ...de matériaux et couleurs - 2 = Ivoire clair
Enveloppe 170989 | Niveau 2 | Enveloppe | 170989 | 366 | 9000 | 1977773087 | 1977773087 | 1 | 0 | 0429 | 05 | Niveau 2 | no | rectangle | 195.03 | 247.5 | 1.42109e-12 | 90.2655 | 247.5 | 270.265 | HAUT Niveau 2 (Mezzanine 49003) | 12.5 | <aucun> | Niveau 2 (Niveau 2 13545) | <aucun> | 195 | 195 | 247.5 | 247.5 | 1800 | 1800 | 1800 | 48300 | 430000 | Ivoire clair | Ivoire clair | 434430 | 434430 | 9 | 247.5 | 1755.27 | 48270 | 48270 | ...de stratigraphies = default; ...de matériaux et couleurs = Ivoire clair; ...de matériaux et couleurs - 1 = Ivoire clair; ...de matériaux et couleurs - 2 = Ivoire clair
Enveloppe 170827 | Niveau 2 | Enveloppe | 170827 | 366 | 9000 | 1977773087 | 1977773087 | 1 | 0 | 0426 | 05 | Niveau 2 | no | rectangle | 188.99 | 247.5 | 1.42109e-12 | 90.7017 | 247.5 | 270.702 | HAUT Niveau 2 (Mezzanine 49003) | 12.5 | <aucun> | Niveau 2 (Niveau 2 13545) | <aucun> | 189 | 189 | 247.5 | 247.5 | 1700 | 1700 | 1700 | 46800 | 420000 | Ivoire clair | Ivoire clair | 420976 | 420976 | 9 | 247.5 | 1700.91 | 46775.1 | 46775.1 | ...de stratigraphies = default; ...de matériaux et couleurs = Ivoire clair; ...de matériaux et couleurs - 1 = Ivoire clair; ...de matériaux et couleurs - 2 = Ivoire clair
Enveloppe 171171 | Niveau 2 | Enveloppe | 171171 | 366 | 9000 | 1977773087 | 1977773087 | 1 | 0 | 0432 | 05 | Niveau 2 | no | rectangle | 103.22 | 225 | 1.42109e-12 | 0.100251 | 225 | 180.1 | HAUT Niveau 2 (Mezzanine 49003) | -10 | <aucun> | Niveau 2 (Niveau 2 13545) | <aucun> | 103.2 | 103.2 | 225 | 225 | 900 | 900 | 900 | 23200 | 210000 | Ivoire clair | Ivoire clair | 209021 | 209021 | 9 | 225 | 928.98 | 23224.5 | 23224.5 | ...de stratigraphies = default; ...de matériaux et couleurs = Ivoire clair; ...de matériaux et couleurs - 1 = Ivoire clair; ...de matériaux et couleurs - 2 = Ivoire clair
Enveloppe 166958 | Niveau 2 | Enveloppe | 166958 | 366 | 9000 | 1977773087 | 1977773087 | 0 | 0 | 0407 | 05 | Niveau 2 | no | trapèze | 106.777 | 368.973 | 1.42109e-12 | 90.6576 | 344.26 | 270.658 | HAUT Mezzanine (Couverture 2134) | 0 | Toit783918 | Niveau 2 (Niveau 2 13545) | <aucun> | 106.8 | 109.6 | 369 | 344.3 | 1000 | 1000 | 1100 | 39300 | 350000 | Ivoire clair | Ivoire clair | 354063 | 354063 | 9 | 368.437 | 960.989 | 39340.4 | 39340.4 | ...de stratigraphies = default; ...de matériaux et couleurs = Ivoire clair; ...de matériaux et couleurs - 1 = Ivoire clair; ...de matériaux et couleurs - 2 = Ivoire clair
Enveloppe 159546 | Niveau 2 | Enveloppe | 159546 | 366 | 9000 | 1977773087 | 1977773087 | 1 | 0 | 0382 | 05 | Niveau 2 | no | rectangle | 39.386 | 261.846 | 1.42109e-12 | 135.152 | 261.846 | 315.152 | HAUT Niveau 2 (Mezzanine 49003) | 26.8456 | <aucun> | Niveau 2 (Niveau 2 13545) | <aucun> | 39.4 | 39.4 | 261.8 | 261.8 | 400 | 400 | 400 | 10300 | 90000 | Ivoire clair | Ivoire clair | 92817.4 | 92817.4 | 9 | 261.846 | 354.474 | 10313 | 10313 | ...de stratigraphies = default; ...de matériaux et couleurs = Ivoire clair; ...de matériaux et couleurs - 1 = Ivoire clair; ...de matériaux et couleurs - 2 = Ivoire clair
Enveloppe 159576 | Niveau 2 | Enveloppe | 159576 | 366 | 9000 | 1977773087 | 1977773087 | 1 | 0 | 0383 | 05 | Niveau 2 | no | rectangle | 48.4938 | 261.846 | 1.42109e-12 | 136.038 | 261.846 | 316.038 | HAUT Niveau 2 (Mezzanine 49003) | 26.8456 | <aucun> | Niveau 2 (Niveau 2 13545) | <aucun> | 48.5 | 48.5 | 261.8 | 261.8 | 400 | 400 | 400 | 12700 | 110000 | Ivoire clair | Ivoire clair | 114281 | 114281 | 9 | 261.846 | 436.445 | 12697.9 | 12697.9 | ...de stratigraphies = default; ...de matériaux et couleurs = Ivoire clair; ...de matériaux et couleurs - 1 = Ivoire clair; ...de matériaux et couleurs - 2 = Ivoire clair
Enveloppe 159358 | Niveau 2 | Enveloppe | 159358 | 366 | 9000 | 1977773087 | 1977773087 | 0 | 0 | 0380 | 05 | Niveau 2 | no | rectangle | 208.013 | 261.846 | 1.42109e-12 | 89.9686 | 261.846 | 269.969 | HAUT Niveau 2 (Mezzanine 49003) | 26.8456 | <aucun> | Niveau 2 (Niveau 2 13545) | <aucun> | 208 | 208 | 261.8 | 261.8 | 1900 | 1900 | 1900 | 54500 | 490000 | Ivoire clair | Ivoire clair | 490205 | 490205 | 9 | 261.846 | 1872.11 | 54467.2 | 54467.2 | ...de stratigraphies = default; ...de matériaux et couleurs = Ivoire clair; ...de matériaux et couleurs - 1 = Ivoire clair; ...de matériaux et couleurs - 2 = Ivoire clair
Enveloppe 159427 | Niveau 2 | Enveloppe | 159427 | 366 | 9000 | 1977773087 | 1977773087 | 1 | 0 | 0381 | 05 | Niveau 2 | no | rectangle | 196.514 | 261.846 | 1.42109e-12 | 90.0908 | 261.846 | 270.091 | HAUT Niveau 2 (Mezzanine 49003) | 26.8456 | <aucun> | Niveau 2 (Niveau 2 13545) | <aucun> | 196.5 | 196.5 | 261.8 | 261.8 | 1800 | 1800 | 1800 | 51400 | 460000 | Ivoire clair | Ivoire clair | 463108 | 463108 | 9 | 261.846 | 1768.63 | 51456.4 | 51456.4 | ...de stratigraphies = default; ...de matériaux et couleurs = Ivoire clair; ...de matériaux et couleurs - 1 = Ivoire clair; ...de matériaux et couleurs - 2 = Ivoire clair
Enveloppe 159241 | Niveau 2 | Enveloppe | 159241 | 366 | 9000 | 1977773087 | 1977773087 | 1 | 0 | 0375 | 05 | Niveau 2 | no | rectangle | 198.855 | 261.846 | 1.42109e-12 | 45.1222 | 261.846 | 225.122 | HAUT Niveau 2 (Mezzanine 49003) | 26.8456 | <aucun> | Niveau 2 (Niveau 2 13545) | <aucun> | 198.9 | 198.9 | 261.8 | 261.8 | 1800 | 1800 | 1800 | 52100 | 470000 | Ivoire clair | Ivoire clair | 468623 | 468623 | 9 | 261.846 | 1789.69 | 52069.2 | 52069.2 | ...de stratigraphies = default; ...de matériaux et couleurs = Ivoire clair; ...de matériaux et couleurs - 1 = Ivoire clair; ...de matériaux et couleurs - 2 = Ivoire clair
Enveloppe 159345 | Niveau 2 | Enveloppe | 159345 | 366 | 9000 | 1977773087 | 1977773087 | 0 | 0 | 0378 | 05 | Niveau 2 | no | rectangle | 95.3576 | 261.846 | 1.42109e-12 | 0.630681 | 261.846 | 180.631 | HAUT Niveau 2 (Mezzanine 49003) | 26.8456 | <aucun> | Niveau 2 (Niveau 2 13545) | <aucun> | 95.4 | 95.4 | 261.8 | 261.8 | 900 | 900 | 900 | 25000 | 230000 | Ivoire clair | Ivoire clair | 224721 | 224721 | 9 | 261.846 | 858.219 | 24969 | 24969 | ...de stratigraphies = default; ...de matériaux et couleurs = Ivoire clair; ...de matériaux et couleurs - 1 = Ivoire clair; ...de matériaux et couleurs - 2 = Ivoire clair
Enveloppe 159352 | Niveau 2 | Enveloppe | 159352 | 366 | 9000 | 1977773087 | 1977773087 | 0 | 0 | 0379 | 05 | Niveau 2 | no | rectangle | 39.6719 | 261.846 | 1.42109e-12 | 45.6567 | 261.846 | 225.657 | HAUT Niveau 2 (Mezzanine 49003) | 26.8456 | <aucun> | Niveau 2 (Niveau 2 13545) | <aucun> | 39.7 | 39.7 | 261.8 | 261.8 | 400 | 400 | 400 | 10400 | 90000 | Ivoire clair | Ivoire clair | 93491.1 | 93491.1 | 9 | 261.846 | 357.047 | 10387.9 | 10387.9 | ...de stratigraphies = default; ...de matériaux et couleurs = Ivoire clair; ...de matériaux et couleurs - 1 = Ivoire clair; ...de matériaux et couleurs - 2 = Ivoire clair
Enveloppe 159320 | Niveau 2 | Enveloppe | 159320 | 366 | 9000 | 1977773087 | 1977773087 | 1 | 0 | 0377 | 05 | Niveau 2 | no | rectangle | 101.33 | 261.846 | 1.42109e-12 | 179.569 | 261.846 | 359.569 | HAUT Niveau 2 (Mezzanine 49003) | 26.8456 | <aucun> | Niveau 2 (Niveau 2 13545) | <aucun> | 101.3 | 101.3 | 261.8 | 261.8 | 900 | 900 | 900 | 26500 | 240000 | Ivoire clair | Ivoire clair | 238795 | 238795 | 9 | 261.846 | 911.968 | 26532.8 | 26532.8 | ...de stratigraphies = default; ...de matériaux et couleurs = Ivoire clair; ...de matériaux et couleurs - 1 = Ivoire clair; ...de matériaux et couleurs - 2 = Ivoire clair
Enveloppe 164361 | Niveau 2 | Enveloppe | 164361 | 366 | 9000 | 1977773087 | 1977773087 | 1 | 0 | 0398 | 05 | Niveau 2 | no | rectangle | 43.3962 | 235 | 1.42109e-12 | 0.212577 | 235 | 180.213 | HAUT Niveau 2 (Mezzanine 49003) | 1.42109e-12 | <aucun> | Niveau 2 (Niveau 2 13545) | <aucun> | 43.4 | 43.4 | 235 | 235 | 400 | 400 | 400 | 10200 | 90000 | Ivoire clair | Ivoire clair | 91783 | 91783 | 9 | 235 | 390.566 | 10198.1 | 10198.1 | ...de stratigraphies = default; ...de matériaux et couleurs = Ivoire clair; ...de matériaux et couleurs - 1 = Ivoire clair; ...de matériaux et couleurs - 2 = Ivoire clair
Enveloppe 163764 | Niveau 2 | Enveloppe | 163764 | 366 | 9000 | 1977773087 | 1977773087 | 1 | 0 | 0393 | 05 | Niveau 2 | no | rectangle | 160.884 | 235 | 1.42109e-12 | 0.176298 | 235 | 180.176 | HAUT Niveau 2 (Mezzanine 49003) | 1.42109e-12 | <aucun> | Niveau 2 (Niveau 2 13545) | <aucun> | 160.9 | 160.9 | 235 | 235 | 1400 | 1400 | 1400 | 37800 | 340000 | Ivoire clair | Ivoire clair | 340271 | 340271 | 9 | 235 | 1447.96 | 37807.8 | 37807.8 | ...de stratigraphies = default; ...de matériaux et couleurs = Ivoire clair; ...de matériaux et couleurs - 1 = Ivoire clair; ...de matériaux et couleurs - 2 = Ivoire clair
Enveloppe 150052 | Niveau 2 | Enveloppe | 150052 | 366 | 9000 | 1977773087 | 1977773087 | 0 | 0 | 0324 | 05 | Niveau 2 | no | rectangle | 198.091 | 235 | 1.42109e-12 | 90.9445 | 235 | 270.945 | HAUT Niveau 2 (Mezzanine 49003) | 0 | <aucun> | Niveau 2 (Niveau 2 13545) | <aucun> | 198.1 | 198.1 | 235 | 235 | 1800 | 1800 | 1800 | 46600 | 420000 | Ivoire clair | Ivoire clair | 418962 | 145269 | 9 | 235 | 1782.82 | 46551.3 | 16141 | ...de stratigraphies = default; ...de matériaux et couleurs = Ivoire clair; ...de matériaux et couleurs - 1 = Ivoire clair; ...de matériaux et couleurs - 2 = Ivoire clair
Enveloppe 465629 | Niveau 2 | Enveloppe | 465629 | 366 | 9000 | 1977773087 | 1977773087 | 0 | 1 | 0798 | 05 | Niveau 2 | no | rectangle | 97.8178 | 265.062 | -1.95399e-11 | 89.9289 | 265.062 | 269.929 | HAUT Mezzanine (Couverture 2134) | -249.641 | <aucun> | Niveau 2 (Niveau 2 13545) | <aucun> | 97.8 | 97.8 | 265.1 | 265.1 | 800 | 800 | 800 | 25900 | 230000 | Ivoire clair | Ivoire clair | 233350 | 233350 | 9 | 265.062 | 880.36 | 25927.7 | 25927.7 | ...de stratigraphies = default; ...de matériaux et couleurs = Ivoire clair; ...de matériaux et couleurs - 1 = Ivoire clair; ...de matériaux et couleurs - 2 = Ivoire clair
Enveloppe courbe 162928 | Niveau 2 | Enveloppe courbe | 162928 | 367 | 9001 | -746779066 | -746779066 | 1 | 0 | 06 | 05 | Niveau 2 | no | trapèze | 71.2227 | 408.607 | 0 | 46.5571 | 432.403 | 226.557 | HAUT Mezzanine (Couverture 2134) | 0 | <aucun> | Niveau 2 (Niveau 2 13545) | <aucun> | 71.3 | 75.1 | 432.4 | 408.6 | 400 | 600 | 800 | 30900 | 280000 | Blanc | Blanc | 275587 | 275587 | 8.92837 | 433.38 | 635.902 | 30866.5 | 30866.5 | ...de matériaux et couleurs = Blanc; ...de matériaux et couleurs - 1 = Blanc; ...de matériaux et couleurs - 2 = Blanc; ...de stratigraphies = default | IFC_Pset_Géométrie - Rayon: 87.6506 cm; Point arc: [-793,3; -70,8] cm; Centre: [-717,4; -104,7] cm; Angle de la Tangente: 20.702 deg
Enveloppe courbe 170398 | Niveau 2 | Enveloppe courbe | 170398 | 367 | 9001 | -746779066 | -746779066 | 1 | 0 | 13 | 05 | Niveau 2 | no | rectangle | 34.0407 | 183 | 0 | 12.8689 | 183 | 192.869 | HAUT Niveau 2 (Mezzanine 49003) | -52 | <aucun> | Niveau 2 (Niveau 2 13545) | <aucun> | 34 | 34 | 183 | 183 | 200 | 300 | 300 | 6200 | 60000 | Blanc | Blanc | 55919.4 | 55919.4 | 8.97662 | 183 | 305.571 | 6229.45 | 6229.45 | ...de matériaux et couleurs = Blanc; ...de matériaux et couleurs - 1 = Blanc; ...de matériaux et couleurs - 2 = Blanc; ...de stratigraphies = default | IFC_Pset_Géométrie - Rayon: 151.558 cm; Point arc: [-703,3; -9,9] cm; Centre: [-695,9; -156,8] cm; Angle de la Tangente: 3.85789 deg
Enveloppe courbe 170424 | Niveau 2 | Enveloppe courbe | 170424 | 367 | 9001 | -746779066 | -746779066 | 0 | 0 | 14 | 05 | Niveau 2 | no | rectangle | 25.6132 | 200 | 0 | 10.8307 | 200 | 190.831 | HAUT Niveau 2 (Mezzanine 49003) | -35 | <aucun> | Niveau 2 (Niveau 2 13545) | <aucun> | 25.6 | 25.6 | 200 | 200 | 100 | 200 | 200 | 5100 | 50000 | Blanc | Blanc | 46034.6 | 46034.6 | 8.98651 | 200 | 230.173 | 5122.64 | 5122.64 | ...de matériaux et couleurs = Blanc; ...de matériaux et couleurs - 1 = Blanc; ...de matériaux et couleurs - 2 = Blanc; ...de stratigraphies = default | IFC_Pset_Géométrie - Rayon: 135.497 cm; Point arc: [-674,5; -9,5] cm; Centre: [-675,1; -140,5] cm; Angle de la Tangente: 2.83879 deg

# IfcWallStandardCase: default 93, Enveloppe courbe 162722
In: Niveau 2
Type - Material: <aucun> 9.3 cm
Description: Enveloppe courbe; Group: ...de matériaux et couleurs = Blanc; ...de matériaux et couleurs - 1 = Blanc; ...de matériaux et couleurs - 2 = Blanc; ...de stratigraphies = default
__RECOGNIZE__ - ID: 162722; TPLG: 367; TPLG_OD: 9001; GENERATE: 1
CTLG_EXTERNAL_LINK - 0, DocType: 2; 0, Tag: 0; 0, Crc: -746779066; 1, DocType: 2; 1, Tag: 100; 1, Crc: -746779066; 2, DocType: 2; 2, Tag: 200; 2, Crc: -746779066; 3, DocType: 9; 3, Tag: 0; 3, Crc: 581392451
IFC_PSET_PolygonOffset - polygonOffsetFactor: 2; polygonOffsetUnits: 2
IFC_Pset_Alignment - Alignment: 1
IFC_Pset_Strat_Detail_Align - ExternalFace: 0
IFC_Pset_Caractéristiques - ID: 162722; Numérotation: 05; Numéro niveau: 05; Titre niveau: Niveau 2; Stratigraphie: default [93,00]; Épaisseur: 9.3 cm; Épaisseur VARIABLE: no
IFC_Pset_Caractéristiques_FRUIT - Fruit: no; Taille: 0 cm
IFC_Pset_Géométrie_P1 (POINT initial) - Hauteur: 432.403 cm; Cote: 0 cm; Angle XY: 16.594 deg
IFC_Pset_Géométrie_P2 (POINT final) - Hauteur: 415.005 cm; Cote: 0 cm; Angle XY: 196.594 deg
IFC_Pset_Géométrie - Rayon: 109.504 cm; Point arc: [-763,1; -32,7] cm; Centre: [-693,9; -111,5] cm; Angle de la Tangente: 5.63467 deg; Forme en Élévation: trapèze; Longueur: 31.7146 cm; Hauteur: 432.403 cm; Cote: 0 cm
IFC_Pset_Système de Référence Altimétrique_SUPÉRIEUR - NIVEAU: HAUT Mezzanine (Couverture 2134); delta: 0 cm; delta (P1): 0 cm; delta (P2): 0 cm; sous Niveau: <aucun>
IFC_Pset_Système de Référence Altimétrique_INFÉRIEUR - NIVEAU: Niveau 2 (Niveau 2 13545); delta: 0 cm; delta (P1): 0 cm; delta (P2): 0 cm; sous Niveau: <aucun>
IFC_Pset_Données Métré - Longueur Pied: 31.7 cm; Longueur Tête: 36.2 cm; Hauteur Maximale: 432.4 cm; Hauteur Minimale: 415 cm; Surface en Plan: 200 cm2; Surface Pied: 300 cm2; Surface Tête: 300 cm2; Surface de la Paroi: 13400 cm2; Volume: 120000 cm3
IFC_Pset_Matériaux - Face gauche: Blanc; Face droite: Blanc; Face latérale: Blanc
Pset_WallCommon - Reference: default [93,00] (..\VERTICALES\Default\)
BaseQuantities - GrossVolume: 124390 cm3; NetVolume: 124390 cm3; NominalLength: 31.7146 cm; NominalWidth: 9.25681 cm; NominalHeight: 423.704 cm; GrossFootprintArea: 293.576 cm2; NetFootprintArea: 293.576 cm2; GrossSideArea: 13437.6 cm2; NetSideArea: 13437.6 cm2

# IfcWallStandardCase: default 95, Enveloppe courbe 162672
In: Niveau 2
Type - Material: <aucun> 9.5 cm
Description: Enveloppe courbe; Group: ...de matériaux et couleurs = Blanc; ...de matériaux et couleurs - 1 = Blanc; ...de matériaux et couleurs - 2 = Blanc; ...de stratigraphies = default
__RECOGNIZE__ - ID: 162672; TPLG: 367; TPLG_OD: 9001; GENERATE: 1
CTLG_EXTERNAL_LINK - 0, DocType: 2; 0, Tag: 0; 0, Crc: -746779066; 1, DocType: 2; 1, Tag: 100; 1, Crc: -746779066; 2, DocType: 2; 2, Tag: 200; 2, Crc: -746779066; 3, DocType: 9; 3, Tag: 0; 3, Crc: 1801537073
IFC_PSET_PolygonOffset - polygonOffsetFactor: 2; polygonOffsetUnits: 2
IFC_Pset_Alignment - Alignment: 1
IFC_Pset_Strat_Detail_Align - ExternalFace: 0
IFC_Pset_Caractéristiques - ID: 162672; Numérotation: 04; Numéro niveau: 05; Titre niveau: Niveau 2; Stratigraphie: default [95,00]; Épaisseur: 9.5 cm; Épaisseur VARIABLE: no
IFC_Pset_Caractéristiques_FRUIT - Fruit: no; Taille: 0 cm
IFC_Pset_Géométrie_P1 (POINT initial) - Hauteur: 235 cm; Cote: 0 cm; Angle XY: 27.6545 deg
IFC_Pset_Géométrie_P2 (POINT final) - Hauteur: 235 cm; Cote: 0 cm; Angle XY: 207.655 deg
IFC_Pset_Géométrie - Rayon: 74.584 cm; Point arc: [-736,1; -15,7] cm; Centre: [-711,2; -81,0] cm; Angle de la Tangente: 11.1078 deg; Forme en Élévation: rectangle; Longueur: 35.9989 cm; Hauteur: 235 cm; Cote: 0 cm
IFC_Pset_Système de Référence Altimétrique_SUPÉRIEUR - NIVEAU: HAUT Niveau 2 (Mezzanine 49003); delta: 4.79616e-12 cm; delta (P1): 4.79616e-12 cm; delta (P2): 4.79616e-12 cm; sous Niveau: <aucun>
IFC_Pset_Système de Référence Altimétrique_INFÉRIEUR - NIVEAU: Niveau 2 (Niveau 2 13545); delta: 0 cm; delta (P1): 0 cm; delta (P2): 0 cm; sous Niveau: <aucun>
IFC_Pset_Données Métré - Longueur Pied: 36 cm; Longueur Tête: 36 cm; Hauteur Maximale: 235 cm; Hauteur Minimale: 235 cm; Surface en Plan: 200 cm2; Surface Pied: 400 cm2; Surface Tête: 400 cm2; Surface de la Paroi: 8500 cm2; Volume: 90000 cm3
IFC_Pset_Matériaux - Face gauche: Blanc; Face droite: Blanc; Face latérale: Blanc
Pset_WallCommon - Reference: default [95,00] (..\VERTICALES\Default\)
BaseQuantities - GrossVolume: 79568.8 cm3; NetVolume: 79568.8 cm3; NominalLength: 35.9989 cm; NominalWidth: 9.40559 cm; NominalHeight: 235 cm; GrossFootprintArea: 338.591 cm2; NetFootprintArea: 338.591 cm2; GrossSideArea: 8459.74 cm2; NetSideArea: 8459.74 cm2

# IfcWindow: Default Style Name (12)
Type - ParameterTakesPrecedence: no; Sizeable: yes
Description: _VTO_Baie
__RECOGNIZE__ - TPLG: 114; TPLG_OD: 9006; GENERATE: 1
CTLG_EXTERNAL_LINK - 1, DocType: 2
IFC_PSET_PolygonOffset - polygonOffsetFactor: 2; polygonOffsetUnits: 2
IFC_Pset_Géométrie_Allège - Hauteur: 0 cm; Stratigraphie: ...; Épaisseur: 0 cm
IFC_Pset_Géométrie_Ébrasement - Côté supérieur: no; Côté INFÉRIEUR: no; Épaisseur latérale gauche: 0 cm; Épaisseur latérale droite: 0 cm; Épiasseur latérale supérieure: 0 cm; Épaisseur intérieur: 0 cm
IFC_Pset_Géométrie_Seuil - Décalage séparation: 0 cm
IFC_Pset_Géométrie_Chambranle - Épaisseur Chambranle intérieur: 0 cm; Longueur Chambranle intérieur: 0 cm; Superposition Chambranle intérieur: 0 cm; Épaisseur Intrados: 0 cm; Décalage séparation intrados: 0 cm
IFC_Pset_Géométrie_CORNICHE depuis profil - Position: Aucune
IFC_Pset_Géométrie_CORNICHE Extérieure à partir d'un profil - Décalage: 0; Angle: 0 deg; Symétrie: no; Fermer: no; sets with these values: 2
IFC_Pset_Géométrie - Invertir (dte/gche): no; Hauteur 2: 0 cm; Rayon Cercle: 0 cm; Demi-axe horizontal: 0 cm; Demi-axe vertical: 0 cm
IFC_Pset_Géométrie_GRILLE - Offset latéral: 0 cm; Nombre accrochages latéraux: 0; Nombre d'accrochages supérieurs: 0; Nombre accrochages inférieurs: 0
IFC_Pset_Géométrie_Niche - Décalage: 0 cm
IFC_Pset_Système de Référence Altimétrique_INFÉRIEUR - sous Niveau: <aucun>
IFC_Pset_Données Métré - Surface du Seuil intérieur: 0 cm2; Volume du seuil intérieur: 0 cm3; Volume de la Grille: 0 cm3
Name | In | Material | __RECOGNIZE__, ID = IFC_Pset_Caractéristiques, ID | 0, DocType | 0, Tag | 0, Crc | 1, Tag | 1, Crc | 2, DocType | 2, Tag | 2, Crc | Numérotation | Numéro niveau | Titre niveau | IFC_Pset_Géométrie_Ébrasement, Présent = Invertir (intérieur/extérieur) = IFC_Pset_Géométrie_Niche, Présent | Épaisseur extérieure (cm) | Épaisseur diagonale gauche (cm) = Épaisseur diagonale droite (cm) = Épaisseur diagonale inférieure (cm) = Épaisseur diagonale supérieure (cm) = Appui extérieur (cm) = Côté latéral externe (cm) = Côté latéral interne (cm) | Type | IFC_Pset_Géométrie_Seuil, Épaisseur (cm) = Épaisseur interne (cm) | Appui intérieur (cm) | IFC_Pset_Géométrie_Chambranle, Position | Épaisseur Chambranle extérieur (cm) = Superposition Chambranle extérieur (cm) = Épaisseur Intrados extérieur (cm) | Largeur Chambranle extérieur (cm) | IFC_Pset_Géométrie_CORNICHE depuis profil, sets with these values = IFC_Pset_Géométrie_BASE Extérieure à partir d'un profil, sets with these values | IFC_Pset_Géométrie_BASE Extérieure à partir d'un profil, Angle (deg) | IFC_Pset_Géométrie_BASE Extérieure à partir d'un profil, Symétrie | IFC_Pset_Géométrie_BASE Extérieure à partir d'un profil, Côté (cm) | Côté extérieur | Forme | Largeur (cm) | Hauteur (cm) | Rayon Arc (cm) | décalage (cm) | Décalage supérieur (cm) | Décalage inférieur (cm) | Stratigraphie | IFC_Pset_Géométrie_Niche, Épaisseur (cm) | Alignement | NIVEAU | delta (cm) | Surface de l'Ouverture (cm2) | Surface de l'Ébrasement (cm2) | Surface du Seuil (cm2) | Volume du seuil (cm3) | Surface de la Niche (cm2) | Surface de la Grille (cm2) | 3, DocType | 3, Tag | 3, Crc | 4, DocType | 4, Tag | 4, Crc | Modèle Grille | IFC_Pset_Géométrie_GRILLE, Position | Cadre externe = Grillage
Baie 78728 | Rez-de-Jardin | Bleu pastel | 78728 | 2 | 0 | -746779066 | 26 | -654192498 | 9 | 211 | -732809594 | 024 | 02 | Rez-de-Jardin | no | 0 | 0 | Aucun | 0 | 0 | Extérieur | 1 | 8 | 2 | 0 | no | 0 | 1 | Rectangle | 84 | 204 | 0 | 0 | 0 | 0 | Paroi en béton armé [120,00] | 12 | Intérieur | Rez-de-Jardin (Rez-de-Jardin 15545) | 0.546045 | 17100 | 0 | 0 | 0 | 0 | 0 | IFC_Pset_Matériaux - Chambranle Externe: Bleu pastel
Baie 230324 | Rez-de-Jardin | Brèche oniciata | 230324 | 2 | 0 | -746779066 | 20 | 1141262141 | 9 | 211 | -1554559915 | 045 | 02 | Rez-de-Jardin | no | 0 | 0 | Aucun | 0 | 0 | Aucun | 0 | 0 |  | 90 | yes | 8 | 0 | Arc + Rectangle | 98.4571 | 220.925 | 12.4812 | 0 | 0 | 0 | default [80,00] | 8 | Intérieur | Rez-de-Jardin (Rez-de-Jardin 15545) | 0 | 22600 | 0 | 0 | 0 | 0 | 0 | 5 | 700 | 1544883754 | IFC_Pset_Géométrie_Base depuis profil - Position: Extérieur; IFC_Pset_Géométrie_BASE Extérieure à partir d'un profil - Profil: Base100x80mm (..\Base\); Décalage: [0,00; 0,00] mm; IFC_Pset_Géométrie_BASE Intérieure à partir d'un profil - Angle: 0 deg; Symétrie: no; Côté: 0 cm; IFC_Pset_Matériaux - Base Externe: Brèche oniciata
Baie 351619 | Rez-de-Jardin | Blanc de sécurité | 351619 | 3 | 300 | 1785580957 | 0 | -746779066 | 2 | 302 | -1004120743 | 049 | 02 | Rez-de-Jardin | no | 0 | 0 | Aucun | 0 | 0 | Aucun | 0 | 0 | 2 | 0 | no | 0 | 0 | Arc + Rectangle | 100.156 | 102.581 | 11.5629 | 0 | -2 | -4 | default [80,00] | 8 | Intérieur | Rez-de-Jardin (Rez-de-Jardin 15545) | 120.108 | 11000 | 0 | 0 | 0 | 0 | 10400 | 2 | 312 | -1004120743 | 9 | 211 | -1554559915 | Grille [AR] BC[V] | Centre | Blanc de sécurité
Baie 353071 | Rez-de-Jardin | Blanc de sécurité | 353071 | 3 | 300 | 1785580957 | 0 | -746779066 | 2 | 302 | -1004120743 | 051 | 02 | Rez-de-Jardin | no | 0 | 0 | Aucun | 0 | 0 | Aucun | 0 | 0 | 2 | 0 | no | 0 | 0 | Arc + Rectangle | 100.144 | 102.581 | 11.5615 | 0 | -2 | -4 | default [80,00] | 8 | Intérieur | Rez-de-Jardin (Rez-de-Jardin 15545) | 120.131 | 11000 | 0 | 0 | 0 | 0 | 10400 | 2 | 312 | -1004120743 | 9 | 211 | -1554559915 | Grille [AR] BC[V] | Centre | Blanc de sécurité
Baie 351620 | Rez-de-Jardin | Blanc de sécurité | 351620 | 3 | 300 | 1785580957 | 0 | -746779066 | 2 | 302 | -1004120743 | 050 | 02 | Rez-de-Jardin | no | 0 | 0 | Aucun | 0 | 0 | Aucun | 0 | 0 | 2 | 0 | no | 0 | 0 | Arc + Rectangle | 100.553 | 102.581 | 11.6087 | 0 | -2 | -4 | default [80,00] | 8 | Intérieur | Rez-de-Jardin (Rez-de-Jardin 15545) | 120.151 | 11100 | 0 | 0 | 0 | 0 | 10500 | 2 | 312 | -1004120743 | 9 | 211 | -1554559915 | Grille [AR] BC[V] | Centre | Blanc de sécurité
Baie 351618 | Rez-de-Jardin | Blanc de sécurité | 351618 | 3 | 300 | 1785580957 | 0 | -746779066 | 2 | 302 | -1004120743 | 048 | 02 | Rez-de-Jardin | no | 0 | 0 | Aucun | 0 | 0 | Aucun | 0 | 0 | 2 | 0 | no | 0 | 0 | Arc + Rectangle | 100.657 | 102.581 | 11.6206 | 0 | -2 | -4 | default [80,00] | 8 | Intérieur | Rez-de-Jardin (Rez-de-Jardin 15545) | 119.575 | 11100 | 0 | 0 | 0 | 0 | 10500 | 2 | 312 | -1004120743 | 9 | 211 | -1554559915 | Grille [AR] BC[V] | Centre | Blanc de sécurité
Baie 363228 | Rez-de-Jardin | Blanc de sécurité | 363228 | 3 | 300 | 1785580957 | 0 | -746779066 | 2 | 302 | -1004120743 | 057 | 02 | Rez-de-Jardin | no | 0 | 0 | Aucun | 0 | 0 | Aucun | 0 | 0 | 2 | 0 | no | 0 | 1 | Arc + Rectangle | 100.412 | 102.581 | 11.5924 | 5 | -2 | -4 | default [80,00] | 8 | Intérieur | Rez-de-Jardin (Rez-de-Jardin 15545) | 118.194 | 11100 | 0 | 0 | 0 | 0 | 10500 | 2 | 312 | -1004120743 | 9 | 211 | -1554559915 | Grille [AR] BC[V] | Intérieur | Blanc de sécurité
Baie 363229 | Rez-de-Jardin | Blanc de sécurité | 363229 | 3 | 300 | 1785580957 | 0 | -746779066 | 2 | 302 | -1004120743 | 058 | 02 | Rez-de-Jardin | no | 0 | 0 | Aucun | 0 | 0 | Aucun | 0 | 0 | 2 | 0 | no | 0 | 1 | Arc + Rectangle | 102.254 | 102.581 | 11.805 | 8 | -2 | -4 | default [80,00] | 8 | Intérieur | Rez-de-Jardin (Rez-de-Jardin 15545) | 119 | 11300 | 0 | 0 | 0 | 0 | 10700 | 2 | 312 | -1004120743 | 9 | 211 | -1554559915 | Grille [AR] BC[V] | Centre | Blanc de sécurité
Baie 363235 | Rez-de-Jardin | Blanc de sécurité | 363235 | 3 | 300 | 1785580957 | 0 | -746779066 | 2 | 302 | -1004120743 | 060 | 02 | Rez-de-Jardin | no | 0 | 0 | Aucun | 0 | 0 | Aucun | 0 | 0 | 2 | 0 | no | 0 | 1 | Arc + Rectangle | 100.035 | 102.581 | 11.5489 | 8 | -2 | -4 | default [80,00] | 8 | Intérieur | Rez-de-Jardin (Rez-de-Jardin 15545) | 119.027 | 11000 | 0 | 0 | 0 | 0 | 10400 | 2 | 312 | -1004120743 | 9 | 211 | -1554559915 | Grille [AR] BC[V] | Intérieur | Blanc de sécurité
Baie 363234 | Rez-de-Jardin | Blanc de sécurité | 363234 | 3 | 300 | -92539492 | 0 | -746779066 | 2 | 302 | -1004120743 | 059 | 02 | Rez-de-Jardin | no | 0 | 0 | Aucun | 0 | 0 | Aucun | 0 | 0 | 2 | 0 | no | 0 | 1 | Rectangle | 89.5165 | 72.7108 | 0 | 7 | 0 | 0 | default [80,00] | 8 | Intérieur | Rez-de-Jardin (Rez-de-Jardin 15545) | 188.096 | 6500 | 0 | 0 | 0 | 0 | 6500 | 2 | 312 | -1004120743 | 9 | 211 | -1554559915 | Grille [R] BR[V] | Centre | Blanc de sécurité
Baie 351615 | Rez-de-Jardin | Blanc de sécurité | 351615 | 3 | 300 | 1785580957 | 0 | -746779066 | 2 | 302 | -1004120743 | 047 | 02 | Rez-de-Jardin | no | 0 | 0 | Aucun | 0 | 0 | Aucun | 0 | 0 | 2 | 0 | no | 0 | 0 | Arc + Rectangle | 100.412 | 102.581 | 11.5924 | 10 | -2 | -4 | default [80,00] | 8 | Intérieur | Rez-de-Jardin (Rez-de-Jardin 15545) | 119.019 | 11100 | 0 | 0 | 0 | 0 | 10500 | 2 | 312 | -1004120743 | 9 | 211 | -1554559915 | Grille [AR] BC[V] | Centre | Blanc de sécurité
Baie 118808 | Niveau 1 | Brèche oniciata | 118808 | 2 | 0 | -746779066 | 15 | 1141262141 | 9 | 211 | -1765334021 | 037 | 04 | Niveau 1 | yes | 16.5 | 2 | Unique | 3 | 5 | Aucun | 0 | 0 | 2 | 0 | no | 0 | 1 | Arc + Rectangle | 125.71 | 112.287 | 16.8469 | 0 | 0 | 0 | default [165,00] | 16.5 | Extérieur | Niveau 1 (Niveau 1 2343) | 119.916 | 15700 | 14200 | 5600 | 20000 | 15700 | 0 | IFC_Pset_Géométrie_Ébrasement - Données: [a : 165,00; b [gche]: 0,00; b [dte]: 0,00; b [sup]: 0,00; c [gche]: 20,00; c [dte]: 20,00; c [inf]: 20,00; c [sup]: 20,00; d: 0,00] mm; IFC_Pset_Matériaux - Seuil: Brèche oniciata

# IfcWindow: FN fixe 1 section, Fenêtre 728353
In: Niveau 2
Type - ParameterTakesPrecedence: yes; Sizeable: no; Material: Transparent, Blanc trafic
Type - IfcWindowLiningProperties - LiningDepth: 8 cm; LiningThickness: 5 cm
Description: Fenêtre; OverallHeight: 221.677 cm; OverallWidth: 143.935 cm
__RECOGNIZE__ - ID: 728353; TPLG: 101; TPLG_OD: 9004; GENERATE: 1
CTLG_EXTERNAL_LINK - 0, DocType: 3; 0, Tag: 100; 0, Crc: -1535294501; 1, DocType: 2; 1, Tag: 0; 1, Crc: -746779066; 2, DocType: 2; 2, Tag: 102; 2, Crc: -848491367; 3, DocType: 2; 3, Tag: 104; 3, Crc: -623492449
IFC_PSET_PolygonOffset - polygonOffsetFactor: 2; polygonOffsetUnits: 2
IFC_Pset_Caractéristiques - ID: 728353; Numérotation: 114; Numéro niveau: 05; Titre niveau: Niveau 2; Modèle 1re menuiserie: FN fixe 1 section
IFC_Pset_Géométrie_Allège - Hauteur: 0 cm; Stratigraphie: ...; Épaisseur: 0 cm
IFC_Pset_Géométrie_Ébrasement - Présent: no; Côté supérieur: no; Côté INFÉRIEUR: no; Épaisseur extérieure: 0 cm; Épaisseur latérale gauche: 0 cm; Épaisseur latérale droite: 0 cm; Épiasseur latérale supérieure: 0 cm; Épaisseur diagonale gauche: 0 cm; Épaisseur diagonale droite: 0 cm; Épaisseur diagonale inférieure: 0 cm; Épaisseur diagonale supérieure: 0 cm; Épaisseur intérieur: 0 cm
IFC_Pset_Géométrie_Seuil - Type: Aucun; Épaisseur: 0 cm; Épaisseur interne: 0 cm; Décalage séparation: 0 cm; Appui extérieur: 0 cm; Appui intérieur: 0 cm; Côté latéral externe: 0 cm; Côté latéral interne: 0 cm
IFC_Pset_Géométrie_Chambranle - Position: Aucun; Épaisseur Chambranle intérieur: 0 cm; Longueur Chambranle intérieur: 0 cm; Superposition Chambranle intérieur: 0 cm; Épaisseur Intrados: 0 cm; Épaisseur Chambranle extérieur: 0 cm; Largeur Chambranle extérieur: 0 cm; Superposition Chambranle extérieur: 0 cm; Épaisseur Intrados extérieur: 0 cm
IFC_Pset_Géométrie_CORNICHE depuis profil - Position: Aucune; sets with these values: 2
IFC_Pset_Géométrie_CORNICHE Extérieure à partir d'un profil - Décalage: 0; Angle: 0 deg; Symétrie: no; Fermer: no; sets with these values: 2
IFC_Pset_Géométrie_BASE Extérieure à partir d'un profil - Angle: 0 deg; Symétrie: no; Côté: 0 cm; sets with these values: 2
IFC_Pset_Géométrie_1° MENUISERIE - Position: Extérieur; Décalage: 0 cm
IFC_Pset_Géométrie_2° MENUISERIE - Décalage: 0 cm
IFC_Pset_Géométrie - Côté extérieur: 0; Invertir (dte/gche): no; Invertir (intérieur/extérieur): no; Largeur: 143.935 cm; Hauteur: 221.677 cm; Hauteur 2: 0 cm; Rayon Arc: 0 cm; Rayon Cercle: 0 cm; Demi-axe horizontal: 0 cm; Demi-axe vertical: 0 cm
IFC_Pset_Géométrie_GRILLE - décalage: 0 cm; Offset latéral: 0 cm; Décalage supérieur: 0 cm; Décalage inférieur: 0 cm; Nombre accrochages latéraux: 0; Nombre d'accrochages supérieurs: 0; Nombre accrochages inférieurs: 0
IFC_Pset_Système de Référence Altimétrique_INFÉRIEUR - NIVEAU: Niveau 2 (Niveau 2 13545); delta: -5.00002 cm; sous Niveau: <aucun>
IFC_Pset_Données Métré - Surface 1re Menuiserie: 31900 cm2; Surface Vitre 1re Menuiserie: 24600 cm2; Surface du Cadre de la 1re Menuiserie: 7300 cm2; Surface 2e Menuiserie: 0 cm2; Surface Vitre 2e Menuiserie: 0 cm2; Surface du Cadre de la 2ème Menuiserie: 0 cm2; Surface de l'Ouverture: 31900 cm2; Surface de l'Ébrasement: 0 cm2; Surface du Seuil: 0 cm2; Surface du Seuil intérieur: 0 cm2; Volume du seuil: 0 cm3; Volume du seuil intérieur: 0 cm3; Surface de la Grille: 0 cm2; Volume de la Grille: 0 cm3
IFC_Pset_Matériaux_1° MENUISERIE - Cadre externe: Blanc trafic; Verre: Transparent
Pset_WindowCommon - Reference: FN fixe 1 section (..\Menuiserie classique\Fenêtre et Balcon\) <aucun>

# IfcWindow: FN triandulaire_1, Fenêtre 1533941
In: Rez-de-Jardin
Type - ParameterTakesPrecedence: no; Sizeable: no; Material: Transparent, Blanc trafic
Type - IfcWindowLiningProperties - LiningDepth: 6 cm; LiningThickness: 4 cm
Type - IfcWindowPanelProperties - OperationType: FIXEDCASEMENT; FrameDepth: 6 cm; FrameThickness: 4 cm
Description: Fenêtre; OverallHeight: 90 cm; OverallWidth: 135.204 cm
__RECOGNIZE__ - ID: 1533941; TPLG: 101; TPLG_OD: 9004; GENERATE: 1
CTLG_EXTERNAL_LINK - 0, DocType: 3; 0, Tag: 100; 0, Crc: 581215175; 1, DocType: 2; 1, Tag: 0; 1, Crc: -746779066; 2, DocType: 2; 2, Tag: 102; 2, Crc: 1192038750; 3, DocType: 2; 3, Tag: 104; 3, Crc: -623492449
IFC_PSET_PolygonOffset - polygonOffsetFactor: 2; polygonOffsetUnits: 2
IFC_Pset_Caractéristiques - ID: 1533941; Numérotation: 127; Numéro niveau: 02; Titre niveau: Rez-de-Jardin; Modèle 1re menuiserie: FN triandulaire_1
IFC_Pset_Géométrie_Allège - Hauteur: 0 cm; Stratigraphie: ...; Épaisseur: 0 cm
IFC_Pset_Géométrie_Ébrasement - Présent: no; Côté supérieur: no; Côté INFÉRIEUR: no; Épaisseur extérieure: 0 cm; Épaisseur latérale gauche: 0 cm; Épaisseur latérale droite: 0 cm; Épiasseur latérale supérieure: 0 cm; Épaisseur diagonale gauche: 0 cm; Épaisseur diagonale droite: 0 cm; Épaisseur diagonale inférieure: 0 cm; Épaisseur diagonale supérieure: 0 cm; Épaisseur intérieur: 0 cm
IFC_Pset_Géométrie_Seuil - Type: Aucun; Épaisseur: 0 cm; Épaisseur interne: 0 cm; Décalage séparation: 0 cm; Appui extérieur: 0 cm; Appui intérieur: 0 cm; Côté latéral externe: 0 cm; Côté latéral interne: 0 cm
IFC_Pset_Géométrie_Chambranle - Position: Aucun; Épaisseur Chambranle intérieur: 0 cm; Longueur Chambranle intérieur: 0 cm; Superposition Chambranle intérieur: 0 cm; Épaisseur Intrados: 0 cm; Épaisseur Chambranle extérieur: 0 cm; Largeur Chambranle extérieur: 0 cm; Superposition Chambranle extérieur: 0 cm; Épaisseur Intrados extérieur: 0 cm
IFC_Pset_Géométrie_CORNICHE depuis profil - Position: Aucune; sets with these values: 2
IFC_Pset_Géométrie_CORNICHE Extérieure à partir d'un profil - Décalage: 0; Angle: 0 deg; Symétrie: no; Fermer: no; sets with these values: 2
IFC_Pset_Géométrie_BASE Extérieure à partir d'un profil - Angle: 0 deg; Symétrie: no; Côté: 0 cm; sets with these values: 2
IFC_Pset_Géométrie_1° MENUISERIE - Position: Intérieur; Décalage: -8 cm
IFC_Pset_Géométrie_2° MENUISERIE - Décalage: 0 cm
IFC_Pset_Géométrie - Côté extérieur: 1; Invertir (dte/gche): no; Invertir (intérieur/extérieur): yes; Largeur: 135.204 cm; Hauteur: 90 cm; Hauteur 2: 0 cm; Rayon Arc: 0 cm; Rayon Cercle: 0 cm; Demi-axe horizontal: 0 cm; Demi-axe vertical: 0 cm
IFC_Pset_Géométrie_GRILLE - décalage: 0 cm; Offset latéral: 0 cm; Décalage supérieur: 0 cm; Décalage inférieur: 0 cm; Nombre accrochages latéraux: 0; Nombre d'accrochages supérieurs: 0; Nombre accrochages inférieurs: 0
IFC_Pset_Système de Référence Altimétrique_INFÉRIEUR - NIVEAU: Rez-de-Jardin (Rez-de-Jardin 15545); delta: 175.556 cm; sous Niveau: <aucun>
IFC_Pset_Données Métré - Surface 1re Menuiserie: 7300 cm2; Surface Vitre 1re Menuiserie: 4400 cm2; Surface du Cadre de la 1re Menuiserie: 2900 cm2; Surface 2e Menuiserie: 0 cm2; Surface Vitre 2e Menuiserie: 0 cm2; Surface du Cadre de la 2ème Menuiserie: 0 cm2; Surface de l'Ouverture: 7300 cm2; Surface de l'Ébrasement: 0 cm2; Surface du Seuil: 0 cm2; Surface du Seuil intérieur: 0 cm2; Volume du seuil: 0 cm3; Volume du seuil intérieur: 0 cm3; Surface de la Grille: 0 cm2; Volume de la Grille: 0 cm3
IFC_Pset_Matériaux_1° MENUISERIE - Cadre externe: Blanc trafic; Verre: Transparent
Pset_WindowCommon - Reference: FN triandulaire_1 (..\FN triangulaire\) <aucun>

# IfcWindow: FN triangulaire_2, Fenêtre 1533942
In: Rez-de-Jardin
Type - ParameterTakesPrecedence: no; Sizeable: no; Material: Transparent, Blanc trafic
Type - IfcWindowLiningProperties - LiningDepth: 6 cm; LiningThickness: 4 cm
Type - IfcWindowPanelProperties - OperationType: FIXEDCASEMENT; FrameDepth: 6 cm; FrameThickness: 4 cm
Description: Fenêtre; OverallHeight: 139.2 cm; OverallWidth: 160.5 cm
__RECOGNIZE__ - ID: 1533942; TPLG: 101; TPLG_OD: 9004; GENERATE: 1
CTLG_EXTERNAL_LINK - 0, DocType: 3; 0, Tag: 100; 0, Crc: -1710214799; 1, DocType: 2; 1, Tag: 0; 1, Crc: -746779066; 2, DocType: 2; 2, Tag: 102; 2, Crc: -848491367; 3, DocType: 2; 3, Tag: 104; 3, Crc: -623492449
IFC_PSET_PolygonOffset - polygonOffsetFactor: 2; polygonOffsetUnits: 2
IFC_Pset_Caractéristiques - ID: 1533942; Numérotation: 128; Numéro niveau: 02; Titre niveau: Rez-de-Jardin; Modèle 1re menuiserie: FN triangulaire_2
IFC_Pset_Géométrie_Allège - Hauteur: 0 cm; Stratigraphie: ...; Épaisseur: 0 cm
IFC_Pset_Géométrie_Ébrasement - Présent: no; Côté supérieur: no; Côté INFÉRIEUR: no; Épaisseur extérieure: 0 cm; Épaisseur latérale gauche: 0 cm; Épaisseur latérale droite: 0 cm; Épiasseur latérale supérieure: 0 cm; Épaisseur diagonale gauche: 0 cm; Épaisseur diagonale droite: 0 cm; Épaisseur diagonale inférieure: 0 cm; Épaisseur diagonale supérieure: 0 cm; Épaisseur intérieur: 0 cm
IFC_Pset_Géométrie_Seuil - Type: Aucun; Épaisseur: 0 cm; Épaisseur interne: 0 cm; Décalage séparation: 0 cm; Appui extérieur: 0 cm; Appui intérieur: 0 cm; Côté latéral externe: 0 cm; Côté latéral interne: 0 cm
IFC_Pset_Géométrie_Chambranle - Position: Aucun; Épaisseur Chambranle intérieur: 0 cm; Longueur Chambranle intérieur: 0 cm; Superposition Chambranle intérieur: 0 cm; Épaisseur Intrados: 0 cm; Épaisseur Chambranle extérieur: 0 cm; Largeur Chambranle extérieur: 0 cm; Superposition Chambranle extérieur: 0 cm; Épaisseur Intrados extérieur: 0 cm
IFC_Pset_Géométrie_CORNICHE depuis profil - Position: Aucune; sets with these values: 2
IFC_Pset_Géométrie_CORNICHE Extérieure à partir d'un profil - Décalage: 0; Angle: 0 deg; Symétrie: no; Fermer: no; sets with these values: 2
IFC_Pset_Géométrie_BASE Extérieure à partir d'un profil - Angle: 0 deg; Symétrie: no; Côté: 0 cm; sets with these values: 2
IFC_Pset_Géométrie_1° MENUISERIE - Position: Intérieur; Décalage: -8 cm
IFC_Pset_Géométrie_2° MENUISERIE - Décalage: 0 cm
IFC_Pset_Géométrie - Côté extérieur: 0; Invertir (dte/gche): no; Invertir (intérieur/extérieur): yes; Largeur: 160.5 cm; Hauteur: 139.2 cm; Hauteur 2: 0 cm; Rayon Arc: 0 cm; Rayon Cercle: 0 cm; Demi-axe horizontal: 0 cm; Demi-axe vertical: 0 cm
IFC_Pset_Géométrie_GRILLE - décalage: 0 cm; Offset latéral: 0 cm; Décalage supérieur: 0 cm; Décalage inférieur: 0 cm; Nombre accrochages latéraux: 0; Nombre d'accrochages supérieurs: 0; Nombre accrochages inférieurs: 0
IFC_Pset_Système de Référence Altimétrique_INFÉRIEUR - NIVEAU: Rez-de-Jardin (Rez-de-Jardin 15545); delta: 126.201 cm; sous Niveau: <aucun>
IFC_Pset_Données Métré - Surface 1re Menuiserie: 19500 cm2; Surface Vitre 1re Menuiserie: 15200 cm2; Surface du Cadre de la 1re Menuiserie: 4300 cm2; Surface 2e Menuiserie: 0 cm2; Surface Vitre 2e Menuiserie: 0 cm2; Surface du Cadre de la 2ème Menuiserie: 0 cm2; Surface de l'Ouverture: 19500 cm2; Surface de l'Ébrasement: 0 cm2; Surface du Seuil: 0 cm2; Surface du Seuil intérieur: 0 cm2; Volume du seuil: 0 cm3; Volume du seuil intérieur: 0 cm3; Surface de la Grille: 0 cm2; Volume de la Grille: 0 cm3
IFC_Pset_Matériaux_1° MENUISERIE - Cadre externe: Blanc trafic; Verre: Transparent
Pset_WindowCommon - Reference: FN triangulaire_2 (..\FN triangulaire\) <aucun>

# IfcWindow: FN triangulaire_3, Fenêtre 1533943
In: Rez-de-Jardin
Type - ParameterTakesPrecedence: no; Sizeable: no; Material: Transparent, Blanc trafic
Type - IfcWindowLiningProperties - LiningDepth: 6 cm; LiningThickness: 4 cm
Type - IfcWindowPanelProperties - OperationType: FIXEDCASEMENT; FrameDepth: 6 cm; FrameThickness: 4 cm
Description: Fenêtre; OverallHeight: 259.5 cm; OverallWidth: 183.766 cm
__RECOGNIZE__ - ID: 1533943; TPLG: 101; TPLG_OD: 9004; GENERATE: 1
CTLG_EXTERNAL_LINK - 0, DocType: 3; 0, Tag: 100; 0, Crc: -218201110; 1, DocType: 2; 1, Tag: 0; 1, Crc: -746779066; 2, DocType: 2; 2, Tag: 102; 2, Crc: -848491367; 3, DocType: 2; 3, Tag: 104; 3, Crc: -623492449
IFC_PSET_PolygonOffset - polygonOffsetFactor: 2; polygonOffsetUnits: 2
IFC_Pset_Caractéristiques - ID: 1533943; Numérotation: 129; Numéro niveau: 02; Titre niveau: Rez-de-Jardin; Modèle 1re menuiserie: FN triangulaire_3
IFC_Pset_Géométrie_Allège - Hauteur: 0 cm; Stratigraphie: ...; Épaisseur: 0 cm
IFC_Pset_Géométrie_Ébrasement - Présent: no; Côté supérieur: no; Côté INFÉRIEUR: no; Épaisseur extérieure: 0 cm; Épaisseur latérale gauche: 0 cm; Épaisseur latérale droite: 0 cm; Épiasseur latérale supérieure: 0 cm; Épaisseur diagonale gauche: 0 cm; Épaisseur diagonale droite: 0 cm; Épaisseur diagonale inférieure: 0 cm; Épaisseur diagonale supérieure: 0 cm; Épaisseur intérieur: 0 cm
IFC_Pset_Géométrie_Seuil - Type: Aucun; Épaisseur: 0 cm; Épaisseur interne: 0 cm; Décalage séparation: 0 cm; Appui extérieur: 0 cm; Appui intérieur: 0 cm; Côté latéral externe: 0 cm; Côté latéral interne: 0 cm
IFC_Pset_Géométrie_Chambranle - Position: Aucun; Épaisseur Chambranle intérieur: 0 cm; Longueur Chambranle intérieur: 0 cm; Superposition Chambranle intérieur: 0 cm; Épaisseur Intrados: 0 cm; Épaisseur Chambranle extérieur: 0 cm; Largeur Chambranle extérieur: 0 cm; Superposition Chambranle extérieur: 0 cm; Épaisseur Intrados extérieur: 0 cm
IFC_Pset_Géométrie_CORNICHE depuis profil - Position: Aucune; sets with these values: 2
IFC_Pset_Géométrie_CORNICHE Extérieure à partir d'un profil - Décalage: 0; Angle: 0 deg; Symétrie: no; Fermer: no; sets with these values: 2
IFC_Pset_Géométrie_BASE Extérieure à partir d'un profil - Angle: 0 deg; Symétrie: no; Côté: 0 cm; sets with these values: 2
IFC_Pset_Géométrie_1° MENUISERIE - Position: Intérieur; Décalage: -8 cm
IFC_Pset_Géométrie_2° MENUISERIE - Décalage: 0 cm
IFC_Pset_Géométrie - Côté extérieur: 0; Invertir (dte/gche): no; Invertir (intérieur/extérieur): no; Largeur: 183.766 cm; Hauteur: 259.5 cm; Hauteur 2: 0 cm; Rayon Arc: 0 cm; Rayon Cercle: 0 cm; Demi-axe horizontal: 0 cm; Demi-axe vertical: 0 cm
IFC_Pset_Géométrie_GRILLE - décalage: 0 cm; Offset latéral: 0 cm; Décalage supérieur: 0 cm; Décalage inférieur: 0 cm; Nombre accrochages latéraux: 0; Nombre d'accrochages supérieurs: 0; Nombre accrochages inférieurs: 0
IFC_Pset_Système de Référence Altimétrique_INFÉRIEUR - NIVEAU: Rez-de-Jardin (Rez-de-Jardin 15545); delta: 8 cm; sous Niveau: <aucun>
IFC_Pset_Données Métré - Surface 1re Menuiserie: 42300 cm2; Surface Vitre 1re Menuiserie: 35900 cm2; Surface du Cadre de la 1re Menuiserie: 6400 cm2; Surface 2e Menuiserie: 0 cm2; Surface Vitre 2e Menuiserie: 0 cm2; Surface du Cadre de la 2ème Menuiserie: 0 cm2; Surface de l'Ouverture: 42300 cm2; Surface de l'Ébrasement: 0 cm2; Surface du Seuil: 0 cm2; Surface du Seuil intérieur: 0 cm2; Volume du seuil: 0 cm3; Volume du seuil intérieur: 0 cm3; Surface de la Grille: 0 cm2; Volume de la Grille: 0 cm3
IFC_Pset_Matériaux_1° MENUISERIE - Cadre externe: Blanc trafic; Verre: Transparent
Pset_WindowCommon - Reference: FN triangulaire_3 (..\FN triangulaire\) <aucun>

# IfcWindow: FN[AR] 1VB[2V]+1F[2V] (6)
In: Rez-de-Jardin
Type - ParameterTakesPrecedence: no; Sizeable: no; Material: Transparent, Brèche oniciata, Aluminium satiné, Blanc trafic
Type - IfcWindowLiningProperties - LiningDepth: 8 cm; LiningThickness: 5 cm
Type - IfcWindowPanelProperties - OperationType: FIXEDCASEMENT; FrameDepth: 0 cm; FrameThickness: 0 cm
Description: Fenêtre
__RECOGNIZE__ - TPLG: 101; TPLG_OD: 9004; GENERATE: 1
CTLG_EXTERNAL_LINK - 0, DocType: 3; 0, Tag: 100; 0, Crc: -1890970506; 1, DocType: 2; 1, Tag: 0; 1, Crc: -746779066; 2, DocType: 2; 2, Tag: 15; 2, Crc: 1141262141; 3, DocType: 2; 3, Tag: 102; 3, Crc: -848491367; 4, DocType: 2; 4, Tag: 104; 4, Crc: -623492449; 5, DocType: 2; 5, Tag: 105; 5, Crc: -848491367; 6, DocType: 2; 6, Tag: 107; 6, Crc: 1305662025
IFC_PSET_PolygonOffset - polygonOffsetFactor: 2; polygonOffsetUnits: 2
IFC_Pset_Caractéristiques - Numéro niveau: 02; Titre niveau: Rez-de-Jardin; Modèle 1re menuiserie: FN[AR] 1VB[2V]+1F[2V]
IFC_Pset_Géométrie_Allège - Hauteur: 0 cm; Stratigraphie: ...; Épaisseur: 0 cm
IFC_Pset_Géométrie_Ébrasement - Côté supérieur: no; Côté INFÉRIEUR: no; Épaisseur latérale gauche: 0 cm; Épaisseur latérale droite: 0 cm; Épiasseur latérale supérieure: 0 cm; Épaisseur intérieur: 0 cm
IFC_Pset_Géométrie_Seuil - Type: Unique; Épaisseur: 3 cm; Épaisseur interne: 3 cm; Décalage séparation: 0 cm; Appui intérieur: 5 cm; Côté latéral externe: 5 cm; Côté latéral interne: 5 cm
IFC_Pset_Géométrie_Chambranle - Position: Aucun; Épaisseur Chambranle intérieur: 0 cm; Longueur Chambranle intérieur: 0 cm; Superposition Chambranle intérieur: 0 cm; Épaisseur Intrados: 0 cm; Épaisseur Chambranle extérieur: 0 cm; Largeur Chambranle extérieur: 0 cm; Superposition Chambranle extérieur: 0 cm; Épaisseur Intrados extérieur: 0 cm
IFC_Pset_Géométrie_CORNICHE depuis profil - Position: Aucune; sets with these values: 2
IFC_Pset_Géométrie_CORNICHE Extérieure à partir d'un profil - Décalage: 0; Angle: 0 deg; Symétrie: no; Fermer: no; sets with these values: 2
IFC_Pset_Géométrie_BASE Extérieure à partir d'un profil - Angle: 0 deg; Symétrie: no; Côté: 0 cm; sets with these values: 2
IFC_Pset_Géométrie_1° MENUISERIE - Position: Extérieur
IFC_Pset_Géométrie_2° MENUISERIE - Décalage: 0 cm
IFC_Pset_Géométrie - Invertir (dte/gche): no; Invertir (intérieur/extérieur): no; Hauteur 2: 0 cm; Rayon Cercle: 0 cm; Demi-axe horizontal: 0 cm; Demi-axe vertical: 0 cm
IFC_Pset_Géométrie_GRILLE - décalage: 0 cm; Offset latéral: 0 cm; Décalage supérieur: 0 cm; Décalage inférieur: 0 cm; Nombre accrochages latéraux: 0; Nombre d'accrochages supérieurs: 0; Nombre accrochages inférieurs: 0
IFC_Pset_Système de Référence Altimétrique_INFÉRIEUR - NIVEAU: Rez-de-Jardin (Rez-de-Jardin 15545); sous Niveau: <aucun>
IFC_Pset_Données Métré - Surface 2e Menuiserie: 0 cm2; Surface Vitre 2e Menuiserie: 0 cm2; Surface du Cadre de la 2ème Menuiserie: 0 cm2; Surface du Seuil intérieur: 0 cm2; Surface de la Grille: 0 cm2; Volume de la Grille: 0 cm3
IFC_Pset_Matériaux - Seuil: Brèche oniciata
IFC_Pset_Matériaux_1° MENUISERIE - Cadre externe: Blanc trafic; Verre: Transparent; Panneau extérieur: Blanc trafic; Poignée: Aluminium satiné
Pset_WindowCommon - Reference: FN[AR] 1VB[2V]+1F[2V] (..\Menuiserie classique\Fenêtre et Balcon\) <aucun>
Name | OverallHeight (cm) | OverallWidth (cm) | __RECOGNIZE__, ID = IFC_Pset_Caractéristiques, ID | Numérotation | Présent | Épaisseur extérieure (cm) | Épaisseur diagonale gauche (cm) = Épaisseur diagonale droite (cm) = Épaisseur diagonale inférieure (cm) = Épaisseur diagonale supérieure (cm) | Appui extérieur (cm) | Décalage (cm) | Côté extérieur | Largeur (cm) | Hauteur (cm) | Rayon Arc (cm) | delta (cm) | Surface 1re Menuiserie (cm2) | Surface Vitre 1re Menuiserie (cm2) | Surface du Cadre de la 1re Menuiserie (cm2) | Surface de l'Ouverture (cm2) | Surface de l'Ébrasement (cm2) | Surface du Seuil (cm2) | Volume du seuil (cm3) = Volume du seuil intérieur (cm3)
Fenêtre 78741 | 106.643 | 97.3438 | 78741 | 029 | no | 0 | 0 | 0 | 2 | 0 | 97.3438 | 97 | 9.64255 | 126.689 | 10100 | 4200 | 5600 | 10100 | 0 | 1400 | 0
Fenêtre 78743 | 109.712 | 106 | 78743 | 030 | no | 0 | 0 | 5.5 | 5 | 0 | 106 | 98 | 11.7123 | 125.9 | 11200 | 5000 | 5900 | 11200 | 0 | 2200 | 10000
Fenêtre 78722 | 105.253 | 104.736 | 78722 | 027 | no | 0 | 0 | 13.5 | 0 | 0 | 104.736 | 97 | 8.25331 | 127.806 | 10700 | 4700 | 5800 | 10700 | 0 | 3000 | 10000
Fenêtre 78724 | 109 | 101.385 | 78724 | 028 | yes | 6 | 1.5 | 8 | 2 | 1 | 101.385 | 98 | 9.49964 | 125.189 | 10700 | 4700 | 5800 | 10700 | 38100 | 2300 | 10000 | IFC_Pset_Géométrie_Ébrasement - Données: [a : 60,00; b [gche]: 0,00; b [dte]: 0,00; b [sup]: 0,00; c [gche]: 15,00; c [dte]: 15,00; c [inf]: 15,00; c [sup]: 15,00; d: 0,00] mm
Fenêtre 73788 | 106.178 | 101.332 | 73788 | 019 | yes | 0 | 3 | 0 | 0.6 | 0 | 100.995 | 94 | 9.00942 | 126.9 | 10400 | 4500 | 5600 | 10300 | 2900 | 1500 | 0 | IFC_Pset_Géométrie_Ébrasement - Données: [a : 0,00; b [gche]: 0,00; b [dte]: 0,00; b [sup]: 0,00; c [gche]: 30,00; c [dte]: 30,00; c [inf]: 30,00; c [sup]: 30,00; d: 0,00] mm
Fenêtre 74104 | 107.086 | 102.153 | 74104 | 024 | yes | 6 | 2 | 20 | -7 | 0 | 102.153 | 96 | 9.0862 | 127 | 10600 | 4600 | 5700 | 10600 | 2900 | 3700 | 10000 | IFC_Pset_Géométrie_Ébrasement - Données: [a : 60,00; b [gche]: 0,00; b [dte]: 0,00; b [sup]: 0,00; c [gche]: 20,00; c [dte]: 20,00; c [inf]: 20,00; c [sup]: 20,00; d: 0,00] mm

# IfcWindow: FN[AR] 1VB[2V]+1F[2V], Fenêtre 74087
In: Rez-de-Jardin
Type - ParameterTakesPrecedence: no; Sizeable: no; Material: Transparent, Brèche oniciata, Blanc de sécurité, Aluminium satiné, Blanc trafic
Type - IfcWindowLiningProperties - LiningDepth: 8 cm; LiningThickness: 5 cm
Type - IfcWindowPanelProperties - OperationType: FIXEDCASEMENT; FrameDepth: 0 cm; FrameThickness: 0 cm
Description: Fenêtre; OverallHeight: 104.673 cm; OverallWidth: 97.8584 cm
__RECOGNIZE__ - ID: 74087; TPLG: 101; TPLG_OD: 9004; GENERATE: 1
CTLG_EXTERNAL_LINK - 0, DocType: 3; 0, Tag: 100; 0, Crc: -1890970506; 1, DocType: 2; 1, Tag: 0; 1, Crc: -746779066; 2, DocType: 2; 2, Tag: 15; 2, Crc: 1141262141; 3, DocType: 2; 3, Tag: 102; 3, Crc: -848491367; 4, DocType: 2; 4, Tag: 104; 4, Crc: -623492449; 5, DocType: 2; 5, Tag: 105; 5, Crc: -1004120743; 6, DocType: 2; 6, Tag: 107; 6, Crc: 1305662025
IFC_PSET_PolygonOffset - polygonOffsetFactor: 2; polygonOffsetUnits: 2
IFC_Pset_Caractéristiques - ID: 74087; Numérotation: 020; Numéro niveau: 02; Titre niveau: Rez-de-Jardin; Modèle 1re menuiserie: FN[AR] 1VB[2V]+1F[2V]
IFC_Pset_Géométrie_Allège - Hauteur: 0 cm; Stratigraphie: ...; Épaisseur: 0 cm
IFC_Pset_Géométrie_Ébrasement - Présent: yes; Côté supérieur: no; Côté INFÉRIEUR: no; Épaisseur extérieure: 6 cm; Épaisseur latérale gauche: 0 cm; Épaisseur latérale droite: 0 cm; Épiasseur latérale supérieure: 0 cm; Épaisseur diagonale gauche: 4 cm; Épaisseur diagonale droite: 4 cm; Épaisseur diagonale inférieure: 4 cm; Épaisseur diagonale supérieure: 4 cm; Épaisseur intérieur: 0 cm; Données: [a : 60,00; b [gche]: 0,00; b [dte]: 0,00; b [sup]: 0,00; c [gche]: 40,00; c [dte]: 40,00; c [inf]: 40,00; c [sup]: 40,00; d: 0,00] mm
IFC_Pset_Géométrie_Seuil - Type: Unique; Épaisseur: 3 cm; Épaisseur interne: 3 cm; Décalage séparation: 0 cm; Appui extérieur: 17 cm; Appui intérieur: 5 cm; Côté latéral externe: 5 cm; Côté latéral interne: 5 cm
IFC_Pset_Géométrie_Chambranle - Position: Aucun; Épaisseur Chambranle intérieur: 0 cm; Longueur Chambranle intérieur: 0 cm; Superposition Chambranle intérieur: 0 cm; Épaisseur Intrados: 0 cm; Épaisseur Chambranle extérieur: 0 cm; Largeur Chambranle extérieur: 0 cm; Superposition Chambranle extérieur: 0 cm; Épaisseur Intrados extérieur: 0 cm
IFC_Pset_Géométrie_CORNICHE depuis profil - Position: Aucune; sets with these values: 2
IFC_Pset_Géométrie_CORNICHE Extérieure à partir d'un profil - Décalage: 0; Angle: 0 deg; Symétrie: no; Fermer: no; sets with these values: 2
IFC_Pset_Géométrie_BASE Extérieure à partir d'un profil - Angle: 0 deg; Symétrie: no; Côté: 0 cm; sets with these values: 2
IFC_Pset_Géométrie_1° MENUISERIE - Position: Extérieur; Décalage: -5 cm
IFC_Pset_Géométrie_2° MENUISERIE - Décalage: 0 cm
IFC_Pset_Géométrie - Côté extérieur: 1; Invertir (dte/gche): no; Invertir (intérieur/extérieur): no; Largeur: 97.8584 cm; Hauteur: 92.8001 cm; Hauteur 2: 0 cm; Rayon Arc: 7.87308 cm; Rayon Cercle: 0 cm; Demi-axe horizontal: 0 cm; Demi-axe vertical: 0 cm
IFC_Pset_Géométrie_GRILLE - décalage: 0 cm; Offset latéral: 0 cm; Décalage supérieur: 0 cm; Décalage inférieur: 0 cm; Nombre accrochages latéraux: 0; Nombre d'accrochages supérieurs: 0; Nombre accrochages inférieurs: 0
IFC_Pset_Système de Référence Altimétrique_INFÉRIEUR - NIVEAU: Rez-de-Jardin (Rez-de-Jardin 15545); delta: 128 cm; sous Niveau: <aucun>
IFC_Pset_Données Métré - Surface 1re Menuiserie: 9900 cm2; Surface Vitre 1re Menuiserie: 4200 cm2; Surface du Cadre de la 1re Menuiserie: 5500 cm2; Surface 2e Menuiserie: 0 cm2; Surface Vitre 2e Menuiserie: 0 cm2; Surface du Cadre de la 2ème Menuiserie: 0 cm2; Surface de l'Ouverture: 9900 cm2; Surface de l'Ébrasement: 3300 cm2; Surface du Seuil: 3300 cm2; Surface du Seuil intérieur: 0 cm2; Volume du seuil: 10000 cm3; Volume du seuil intérieur: 10000 cm3; Surface de la Grille: 0 cm2; Volume de la Grille: 0 cm3
IFC_Pset_Matériaux - Seuil: Brèche oniciata
IFC_Pset_Matériaux_1° MENUISERIE - Cadre externe: Blanc trafic; Verre: Transparent; Panneau extérieur: Blanc de sécurité; Poignée: Aluminium satiné
Pset_WindowCommon - Reference: FN[AR] 1VB[2V]+1F[2V] (..\Menuiserie classique\Fenêtre et Balcon\) <aucun>

# IfcWindow: FN[R] 1VBM 2 DV (2)
In: Niveau 1
Type - OperationType: DOUBLE_PANEL_HORIZONTAL; ParameterTakesPrecedence: yes; Sizeable: no; Material: Transparent, Bleu france, Aluminium satiné
Type - IfcWindowLiningProperties - LiningDepth: 8.3 cm; LiningThickness: 8.3 cm; TransomThickness: 0.1 cm; FirstTransomOffset: 0.722176
Type - IfcWindowPanelProperties - OperationType: FIXEDCASEMENT; PanelPosition: TOP; FrameDepth: 0 cm; FrameThickness: 0 cm
Description: Fenêtre
__RECOGNIZE__ - TPLG: 101; TPLG_OD: 9004; GENERATE: 1
CTLG_EXTERNAL_LINK - 0, DocType: 3; 0, Tag: 100; 0, Crc: -842828742; 1, DocType: 2; 1, Tag: 0; 1, Crc: -746779066; 2, DocType: 2; 2, Tag: 102; 2, Crc: 1181025438; 3, DocType: 2; 3, Tag: 104; 3, Crc: -623492449; 4, DocType: 2; 4, Tag: 107; 4, Crc: -212966465
IFC_PSET_PolygonOffset - polygonOffsetFactor: 2; polygonOffsetUnits: 2
IFC_Pset_Caractéristiques - Numéro niveau: 04; Titre niveau: Niveau 1; Modèle 1re menuiserie: FN[R] 1VBM 2 DV
IFC_Pset_Géométrie_Allège - Hauteur: 0 cm; Stratigraphie: ...; Épaisseur: 0 cm
IFC_Pset_Géométrie_Ébrasement - Présent: no; Côté supérieur: no; Côté INFÉRIEUR: no; Épaisseur extérieure: 0 cm; Épaisseur latérale gauche: 0 cm; Épaisseur latérale droite: 0 cm; Épiasseur latérale supérieure: 0 cm; Épaisseur diagonale gauche: 0 cm; Épaisseur diagonale droite: 0 cm; Épaisseur diagonale inférieure: 0 cm; Épaisseur diagonale supérieure: 0 cm; Épaisseur intérieur: 0 cm
IFC_Pset_Géométrie_Seuil - Type: Aucun; Épaisseur: 0 cm; Épaisseur interne: 0 cm; Décalage séparation: 0 cm; Appui extérieur: 0 cm; Appui intérieur: 0 cm; Côté latéral externe: 0 cm; Côté latéral interne: 0 cm
IFC_Pset_Géométrie_Chambranle - Position: Aucun; Épaisseur Chambranle intérieur: 0 cm; Longueur Chambranle intérieur: 0 cm; Superposition Chambranle intérieur: 0 cm; Épaisseur Intrados: 0 cm; Épaisseur Chambranle extérieur: 0 cm; Largeur Chambranle extérieur: 0 cm; Superposition Chambranle extérieur: 0 cm; Épaisseur Intrados extérieur: 0 cm
IFC_Pset_Géométrie_CORNICHE depuis profil - Position: Aucune; sets with these values: 2
IFC_Pset_Géométrie_CORNICHE Extérieure à partir d'un profil - Décalage: 0; Angle: 0 deg; Symétrie: no; Fermer: no; sets with these values: 2
IFC_Pset_Géométrie_BASE Extérieure à partir d'un profil - Angle: 0 deg; Symétrie: no; Côté: 0 cm; sets with these values: 2
IFC_Pset_Géométrie_1° MENUISERIE - Position: Extérieur; Décalage: 0 cm
IFC_Pset_Géométrie_2° MENUISERIE - Décalage: 0 cm
IFC_Pset_Géométrie - Côté extérieur: 0; Invertir (intérieur/extérieur): no; Hauteur 2: 0 cm; Rayon Arc: 0 cm; Rayon Cercle: 0 cm; Demi-axe horizontal: 0 cm; Demi-axe vertical: 0 cm
IFC_Pset_Géométrie_GRILLE - décalage: 0 cm; Offset latéral: 0 cm; Décalage supérieur: 0 cm; Décalage inférieur: 0 cm; Nombre accrochages latéraux: 0; Nombre d'accrochages supérieurs: 0; Nombre accrochages inférieurs: 0
IFC_Pset_Système de Référence Altimétrique_INFÉRIEUR - NIVEAU: Niveau 1 (Niveau 1 2343); sous Niveau: <aucun>
IFC_Pset_Données Métré - Surface du Cadre de la 1re Menuiserie: 8700 cm2; Surface 2e Menuiserie: 0 cm2; Surface Vitre 2e Menuiserie: 0 cm2; Surface du Cadre de la 2ème Menuiserie: 0 cm2; Surface de l'Ébrasement: 0 cm2; Surface du Seuil: 0 cm2; Surface du Seuil intérieur: 0 cm2; Volume du seuil: 0 cm3; Volume du seuil intérieur: 0 cm3; Surface de la Grille: 0 cm2; Volume de la Grille: 0 cm3
IFC_Pset_Matériaux_1° MENUISERIE - Cadre externe: Bleu france; Verre: Transparent; Poignée: Aluminium satiné
Pset_WindowCommon - Reference: FN[R] 1VBM 2 DV (..\finestra e portafinestra hanna\) <aucun>
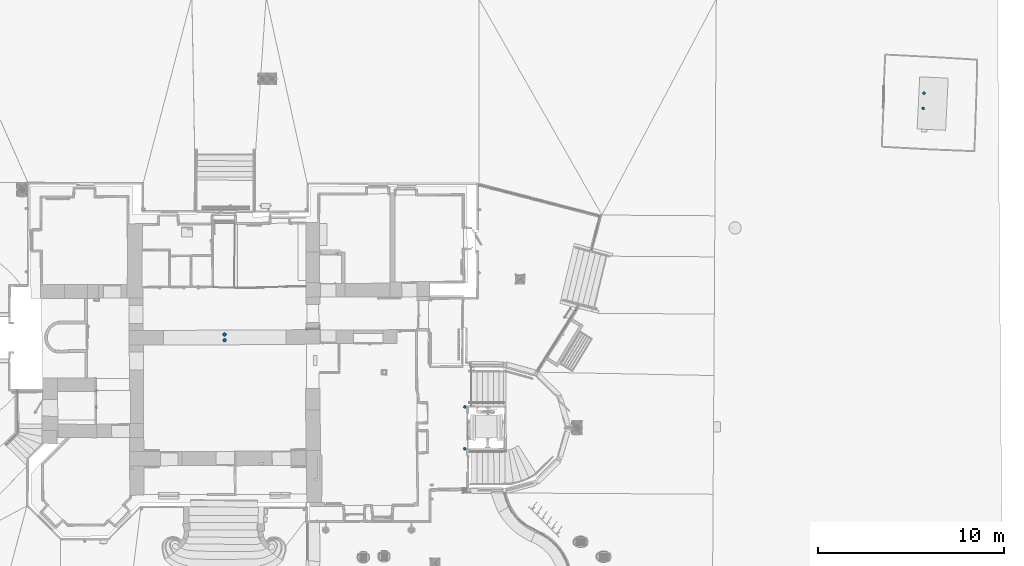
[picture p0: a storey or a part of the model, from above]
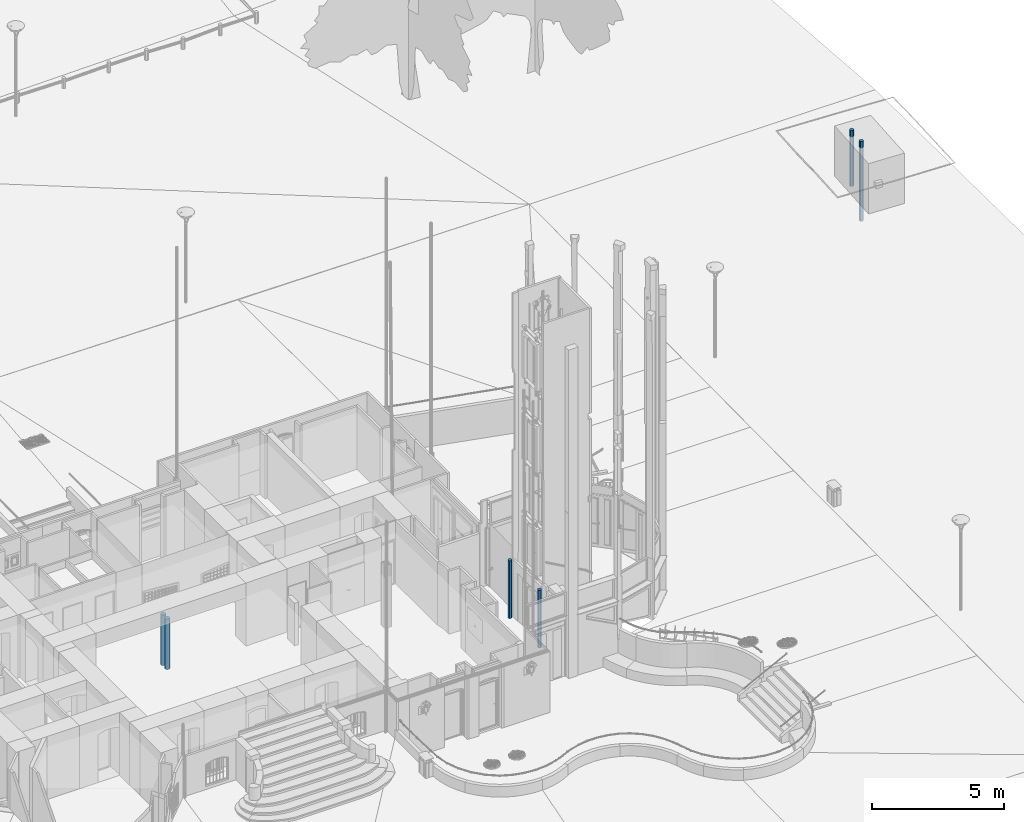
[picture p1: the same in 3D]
Properties of the parts of a building model (IFC2X3), part 35 of 37

# IfcWindow: FN[R] 1VBM 2 DV (2)
Name | OverallHeight (cm) = Hauteur (cm) | OverallWidth (cm) = Largeur (cm) | __RECOGNIZE__, ID = IFC_Pset_Caractéristiques, ID | Numérotation | Invertir (dte/gche) | delta (cm) | Surface 1re Menuiserie (cm2) = Surface de l'Ouverture (cm2) | Surface Vitre 1re Menuiserie (cm2)
Fenêtre 103202 | 239 | 60.6698 | 103202 | 035 | yes | 55.6 | 14500 | 5800
Fenêtre 103205 | 236.5 | 62.559 | 103205 | 036 | no | 56.6 | 14800 | 6100

# IfcWindow: FN[R] 1VB[1V] (2)
In: Niveau 2
Type - OperationType: SINGLE_PANEL; ParameterTakesPrecedence: yes; Sizeable: no; Material: Transparent, Aluminium satiné, Blanc trafic
Type - IfcWindowLiningProperties - LiningDepth: 8 cm; LiningThickness: 5 cm
Type - IfcWindowPanelProperties - OperationType: SIDEHUNGRIGHTHAND; PanelPosition: MIDDLE; FrameDepth: 7 cm; FrameThickness: 5 cm
Description: Fenêtre; OverallHeight: 100.109 cm
__RECOGNIZE__ - TPLG: 101; TPLG_OD: 9004; GENERATE: 1
CTLG_EXTERNAL_LINK - 0, DocType: 3; 0, Tag: 100; 0, Crc: 1251069137; 1, DocType: 2; 1, Tag: 0; 1, Crc: -746779066; 2, DocType: 2; 2, Tag: 102; 2, Crc: -848491367; 3, DocType: 2; 3, Tag: 104; 3, Crc: -623492449; 4, DocType: 2; 4, Tag: 107; 4, Crc: 1305662025
IFC_PSET_PolygonOffset - polygonOffsetFactor: 2; polygonOffsetUnits: 2
IFC_Pset_Caractéristiques - Numéro niveau: 05; Titre niveau: Niveau 2; Modèle 1re menuiserie: FN[R] 1VB[1V]
IFC_Pset_Géométrie_Allège - Hauteur: 0 cm; Stratigraphie: ...; Épaisseur: 0 cm
IFC_Pset_Géométrie_Ébrasement - Présent: no; Côté supérieur: no; Côté INFÉRIEUR: no; Épaisseur extérieure: 0 cm; Épaisseur latérale gauche: 0 cm; Épaisseur latérale droite: 0 cm; Épiasseur latérale supérieure: 0 cm; Épaisseur diagonale gauche: 0 cm; Épaisseur diagonale droite: 0 cm; Épaisseur diagonale inférieure: 0 cm; Épaisseur diagonale supérieure: 0 cm; Épaisseur intérieur: 0 cm
IFC_Pset_Géométrie_Seuil - Type: Aucun; Épaisseur: 0 cm; Épaisseur interne: 0 cm; Décalage séparation: 0 cm; Appui extérieur: 0 cm; Appui intérieur: 0 cm; Côté latéral externe: 0 cm; Côté latéral interne: 0 cm
IFC_Pset_Géométrie_Chambranle - Position: Aucun; Épaisseur Chambranle intérieur: 0 cm; Longueur Chambranle intérieur: 0 cm; Superposition Chambranle intérieur: 0 cm; Épaisseur Intrados: 0 cm; Épaisseur Chambranle extérieur: 0 cm; Largeur Chambranle extérieur: 0 cm; Superposition Chambranle extérieur: 0 cm; Épaisseur Intrados extérieur: 0 cm
IFC_Pset_Géométrie_CORNICHE depuis profil - Position: Aucune; sets with these values: 2
IFC_Pset_Géométrie_CORNICHE Extérieure à partir d'un profil - Décalage: 0; Angle: 0 deg; Symétrie: no; Fermer: no; sets with these values: 2
IFC_Pset_Géométrie_BASE Extérieure à partir d'un profil - Angle: 0 deg; Symétrie: no; Côté: 0 cm; sets with these values: 2
IFC_Pset_Géométrie_1° MENUISERIE - Position: Extérieur; Décalage: -2.5 cm
IFC_Pset_Géométrie_2° MENUISERIE - Décalage: 0 cm
IFC_Pset_Géométrie - Côté extérieur: 1; Invertir (dte/gche): yes; Invertir (intérieur/extérieur): yes; Hauteur: 100.109 cm; Hauteur 2: 0 cm; Rayon Arc: 0 cm; Rayon Cercle: 0 cm; Demi-axe horizontal: 0 cm; Demi-axe vertical: 0 cm
IFC_Pset_Géométrie_GRILLE - décalage: 0 cm; Offset latéral: 0 cm; Décalage supérieur: 0 cm; Décalage inférieur: 0 cm; Nombre accrochages latéraux: 0; Nombre d'accrochages supérieurs: 0; Nombre accrochages inférieurs: 0
IFC_Pset_Système de Référence Altimétrique_INFÉRIEUR - NIVEAU: Niveau 2 (Niveau 2 13545); delta: 94 cm; sous Niveau: <aucun>
IFC_Pset_Données Métré - Surface 2e Menuiserie: 0 cm2; Surface Vitre 2e Menuiserie: 0 cm2; Surface du Cadre de la 2ème Menuiserie: 0 cm2; Surface de l'Ébrasement: 0 cm2; Surface du Seuil: 0 cm2; Surface du Seuil intérieur: 0 cm2; Volume du seuil: 0 cm3; Volume du seuil intérieur: 0 cm3; Surface de la Grille: 0 cm2; Volume de la Grille: 0 cm3
IFC_Pset_Matériaux_1° MENUISERIE - Cadre externe: Blanc trafic; Verre: Transparent; Poignée: Aluminium satiné
Pset_WindowCommon - Reference: FN[R] 1VB[1V] (..\Menuiserie classique\Fenêtre et Balcon\) <aucun>
Name | OverallWidth (cm) = Largeur (cm) | __RECOGNIZE__, ID = IFC_Pset_Caractéristiques, ID | Numérotation | Surface 1re Menuiserie (cm2) = Surface de l'Ouverture (cm2) | Surface Vitre 1re Menuiserie (cm2) | Surface du Cadre de la 1re Menuiserie (cm2)
Fenêtre 176760 | 39.9738 | 176760 | 070 | 4000 | 1200 | 2800
Fenêtre 176759 | 44.1037 | 176759 | 069 | 4400 | 1500 | 2900

# IfcWindow: FN[R] 1VB[1V] (4)
In: Niveau 2
Type - OperationType: SINGLE_PANEL; ParameterTakesPrecedence: yes; Sizeable: no; Material: Transparent, Jaune 255-255-0, Brèche oniciata, Aluminium satiné
Type - IfcWindowLiningProperties - LiningDepth: 8 cm; LiningThickness: 5 cm
Type - IfcWindowPanelProperties - OperationType: SIDEHUNGRIGHTHAND; PanelPosition: MIDDLE; FrameDepth: 7 cm; FrameThickness: 5 cm
Description: Fenêtre
__RECOGNIZE__ - TPLG: 101; TPLG_OD: 9004; GENERATE: 1
CTLG_EXTERNAL_LINK - 0, DocType: 3; 0, Tag: 100; 0, Crc: 1251069137; 1, DocType: 2; 1, Tag: 0; 1, Crc: -746779066; 2, DocType: 2; 2, Tag: 15; 2, Crc: 1141262141; 3, DocType: 2; 3, Tag: 102; 3, Crc: -799740758; 4, DocType: 2; 4, Tag: 104; 4, Crc: -623492449; 5, DocType: 2; 5, Tag: 107; 5, Crc: 1305662025
IFC_PSET_PolygonOffset - polygonOffsetFactor: 2; polygonOffsetUnits: 2
IFC_Pset_Caractéristiques - Numéro niveau: 05; Titre niveau: Niveau 2; Modèle 1re menuiserie: FN[R] 1VB[1V]
IFC_Pset_Géométrie_Allège - Hauteur: 0 cm; Stratigraphie: ...; Épaisseur: 0 cm
IFC_Pset_Géométrie_Ébrasement - Présent: no; Côté supérieur: no; Côté INFÉRIEUR: no; Épaisseur extérieure: 0 cm; Épaisseur latérale gauche: 0 cm; Épaisseur latérale droite: 0 cm; Épiasseur latérale supérieure: 0 cm; Épaisseur diagonale gauche: 0 cm; Épaisseur diagonale droite: 0 cm; Épaisseur diagonale inférieure: 0 cm; Épaisseur diagonale supérieure: 0 cm; Épaisseur intérieur: 0 cm
IFC_Pset_Géométrie_Seuil - Type: Unique; Épaisseur: 3 cm; Épaisseur interne: 3 cm; Décalage séparation: 0 cm; Appui extérieur: 0 cm; Appui intérieur: 11 cm; Côté latéral externe: 0 cm; Côté latéral interne: 0 cm
IFC_Pset_Géométrie_Chambranle - Position: Aucun; Épaisseur Chambranle intérieur: 0 cm; Longueur Chambranle intérieur: 0 cm; Superposition Chambranle intérieur: 0 cm; Épaisseur Intrados: 0 cm; Épaisseur Chambranle extérieur: 0 cm; Largeur Chambranle extérieur: 0 cm; Superposition Chambranle extérieur: 0 cm; Épaisseur Intrados extérieur: 0 cm
IFC_Pset_Géométrie_CORNICHE depuis profil - Position: Aucune; sets with these values: 2
IFC_Pset_Géométrie_CORNICHE Extérieure à partir d'un profil - Décalage: 0; Angle: 0 deg; Symétrie: no; Fermer: no; sets with these values: 2
IFC_Pset_Géométrie_BASE Extérieure à partir d'un profil - Angle: 0 deg; Symétrie: no; Côté: 0 cm; sets with these values: 2
IFC_Pset_Géométrie_1° MENUISERIE - Position: Extérieur; Décalage: 0 cm
IFC_Pset_Géométrie_2° MENUISERIE - Décalage: 0 cm
IFC_Pset_Géométrie - Hauteur 2: 0 cm; Rayon Arc: 0 cm; Rayon Cercle: 0 cm; Demi-axe horizontal: 0 cm; Demi-axe vertical: 0 cm
IFC_Pset_Géométrie_GRILLE - décalage: 0 cm; Offset latéral: 0 cm; Décalage supérieur: 0 cm; Décalage inférieur: 0 cm; Nombre accrochages latéraux: 0; Nombre d'accrochages supérieurs: 0; Nombre accrochages inférieurs: 0
IFC_Pset_Système de Référence Altimétrique_INFÉRIEUR - NIVEAU: Niveau 2 (Niveau 2 13545); sous Niveau: <aucun>
IFC_Pset_Données Métré - Surface 2e Menuiserie: 0 cm2; Surface Vitre 2e Menuiserie: 0 cm2; Surface du Cadre de la 2ème Menuiserie: 0 cm2; Surface de l'Ébrasement: 0 cm2; Surface du Seuil intérieur: 0 cm2; Volume du seuil: 0 cm3; Volume du seuil intérieur: 0 cm3; Surface de la Grille: 0 cm2; Volume de la Grille: 0 cm3
IFC_Pset_Matériaux - Seuil: Brèche oniciata
IFC_Pset_Matériaux_1° MENUISERIE - Cadre externe: Jaune 255-255-0; Verre: Transparent; Poignée: Aluminium satiné
Pset_WindowCommon - Reference: FN[R] 1VB[1V] (..\Menuiserie classique\Fenêtre et Balcon\) <aucun>
Name | OverallHeight (cm) = Hauteur (cm) | OverallWidth (cm) = Largeur (cm) | __RECOGNIZE__, ID = IFC_Pset_Caractéristiques, ID | Numérotation | Côté extérieur | Invertir (dte/gche) | Invertir (intérieur/extérieur) | delta (cm) | Surface 1re Menuiserie (cm2) = Surface de l'Ouverture (cm2) | Surface Vitre 1re Menuiserie (cm2) | Surface du Cadre de la 1re Menuiserie (cm2) | Surface du Seuil (cm2)
Fenêtre 166717 | 168 | 71.4251 | 166717 | 064 | 1 | no | yes | 57 | 12000 | 6800 | 5200 | 1400
Fenêtre 167913 | 110 | 39.6513 | 167913 | 066 | 1 | yes | yes | 56 | 4400 | 1300 | 3000 | 800
Fenêtre 167109 | 110 | 40.1803 | 167109 | 065 | 1 | no | yes | 54 | 4400 | 1400 | 3000 | 800
Fenêtre 164477 | 168 | 70.0844 | 164477 | 063 | 0 | yes | no | 57 | 11800 | 6600 | 5100 | 1400

# IfcWindow: FN[R] 2VB[1P] MM, Fenêtre 121287
In: Niveau 1
Type - ParameterTakesPrecedence: no; Sizeable: no; Material: Transparent, Aluminium satiné, Blanc trafic
Type - IfcWindowLiningProperties - LiningDepth: 8 cm; LiningThickness: 5 cm
Type - IfcWindowPanelProperties - OperationType: FIXEDCASEMENT; FrameDepth: 2 cm; FrameThickness: 2 cm
Description: Fenêtre; OverallHeight: 213.2 cm; OverallWidth: 110.762 cm
__RECOGNIZE__ - ID: 121287; TPLG: 101; TPLG_OD: 9004; GENERATE: 1
CTLG_EXTERNAL_LINK - 0, DocType: 3; 0, Tag: 100; 0, Crc: -137258508; 1, DocType: 2; 1, Tag: 0; 1, Crc: -746779066; 2, DocType: 2; 2, Tag: 102; 2, Crc: -848491367; 3, DocType: 2; 3, Tag: 104; 3, Crc: -623492449; 4, DocType: 2; 4, Tag: 105; 4, Crc: -848491367; 5, DocType: 2; 5, Tag: 107; 5, Crc: 1305662025
IFC_PSET_PolygonOffset - polygonOffsetFactor: 2; polygonOffsetUnits: 2
IFC_Pset_Caractéristiques - ID: 121287; Numérotation: 044; Numéro niveau: 04; Titre niveau: Niveau 1; Modèle 1re menuiserie: FN[R] 2VB[1P] MM
IFC_Pset_Géométrie_Allège - Hauteur: 0 cm; Stratigraphie: ...; Épaisseur: 0 cm
IFC_Pset_Géométrie_Ébrasement - Présent: no; Côté supérieur: no; Côté INFÉRIEUR: no; Épaisseur extérieure: 0 cm; Épaisseur latérale gauche: 0 cm; Épaisseur latérale droite: 0 cm; Épiasseur latérale supérieure: 0 cm; Épaisseur diagonale gauche: 0 cm; Épaisseur diagonale droite: 0 cm; Épaisseur diagonale inférieure: 0 cm; Épaisseur diagonale supérieure: 0 cm; Épaisseur intérieur: 0 cm
IFC_Pset_Géométrie_Seuil - Type: Aucun; Épaisseur: 0 cm; Épaisseur interne: 0 cm; Décalage séparation: 0 cm; Appui extérieur: 0 cm; Appui intérieur: 0 cm; Côté latéral externe: 0 cm; Côté latéral interne: 0 cm
IFC_Pset_Géométrie_Chambranle - Position: Aucun; Épaisseur Chambranle intérieur: 0 cm; Longueur Chambranle intérieur: 0 cm; Superposition Chambranle intérieur: 0 cm; Épaisseur Intrados: 0 cm; Épaisseur Chambranle extérieur: 0 cm; Largeur Chambranle extérieur: 0 cm; Superposition Chambranle extérieur: 0 cm; Épaisseur Intrados extérieur: 0 cm
IFC_Pset_Géométrie_CORNICHE depuis profil - Position: Aucune; sets with these values: 2
IFC_Pset_Géométrie_CORNICHE Extérieure à partir d'un profil - Décalage: 0; Angle: 0 deg; Symétrie: no; Fermer: no; sets with these values: 2
IFC_Pset_Géométrie_BASE Extérieure à partir d'un profil - Angle: 0 deg; Symétrie: no; Côté: 0 cm; sets with these values: 2
IFC_Pset_Géométrie_1° MENUISERIE - Position: Extérieur; Décalage: -4 cm
IFC_Pset_Géométrie_2° MENUISERIE - Décalage: 0 cm
IFC_Pset_Géométrie - Côté extérieur: 0; Invertir (dte/gche): no; Invertir (intérieur/extérieur): no; Largeur: 110.762 cm; Hauteur: 213.2 cm; Hauteur 2: 0 cm; Rayon Arc: 0 cm; Rayon Cercle: 0 cm; Demi-axe horizontal: 0 cm; Demi-axe vertical: 0 cm
IFC_Pset_Géométrie_GRILLE - décalage: 0 cm; Offset latéral: 0 cm; Décalage supérieur: 0 cm; Décalage inférieur: 0 cm; Nombre accrochages latéraux: 0; Nombre d'accrochages supérieurs: 0; Nombre accrochages inférieurs: 0
IFC_Pset_Système de Référence Altimétrique_INFÉRIEUR - NIVEAU: Niveau 1 (Niveau 1 2343); delta: 0.0128504 cm; sous Niveau: <aucun>
IFC_Pset_Données Métré - Surface 1re Menuiserie: 23600 cm2; Surface Vitre 1re Menuiserie: 11300 cm2; Surface du Cadre de la 1re Menuiserie: 11000 cm2; Surface 2e Menuiserie: 0 cm2; Surface Vitre 2e Menuiserie: 0 cm2; Surface du Cadre de la 2ème Menuiserie: 0 cm2; Surface de l'Ouverture: 23600 cm2; Surface de l'Ébrasement: 0 cm2; Surface du Seuil: 0 cm2; Surface du Seuil intérieur: 0 cm2; Volume du seuil: 0 cm3; Volume du seuil intérieur: 0 cm3; Surface de la Grille: 0 cm2; Volume de la Grille: 0 cm3
IFC_Pset_Matériaux_1° MENUISERIE - Cadre externe: Blanc trafic; Verre: Transparent; Panneau extérieur: Blanc trafic; Poignée: Aluminium satiné
Pset_WindowCommon - Reference: FN[R] 2VB[1P] MM (..\Menuiserie classique\Fenêtre et Balcon\) <aucun>

# IfcWindow: FN[R] 2VB[1V] MM, Fenêtre 363231
In: Rez-de-Jardin
Type - OperationType: DOUBLE_PANEL_VERTICAL; ParameterTakesPrecedence: yes; Sizeable: no; Material: Transparent, Blanc de sécurité, Aluminium satiné, Blanc trafic
Type - IfcWindowLiningProperties - LiningDepth: 8 cm; LiningThickness: 5 cm; MullionThickness: 0.1 cm; FirstMullionOffset: 0.5
Type - IfcWindowPanelProperties - OperationType: SIDEHUNGLEFTHAND; PanelPosition: LEFT; FrameDepth: 7 cm; FrameThickness: 5 cm
Description: Fenêtre; OverallHeight: 70.7252 cm; OverallWidth: 90.4607 cm
__RECOGNIZE__ - ID: 363231; TPLG: 101; TPLG_OD: 9004; GENERATE: 1
CTLG_EXTERNAL_LINK - 0, DocType: 3; 0, Tag: 100; 0, Crc: -1547682682; 1, DocType: 3; 1, Tag: 300; 1, Crc: -92539492; 2, DocType: 2; 2, Tag: 0; 2, Crc: -746779066; 3, DocType: 2; 3, Tag: 102; 3, Crc: -848491367; 4, DocType: 2; 4, Tag: 104; 4, Crc: -623492449; 5, DocType: 2; 5, Tag: 107; 5, Crc: 1305662025; 6, DocType: 2; 6, Tag: 302; 6, Crc: -1004120743; 7, DocType: 2; 7, Tag: 312; 7, Crc: -1004120743
IFC_PSET_PolygonOffset - polygonOffsetFactor: 2; polygonOffsetUnits: 2
IFC_Pset_Caractéristiques - ID: 363231; Numérotation: 074; Numéro niveau: 02; Titre niveau: Rez-de-Jardin; Modèle 1re menuiserie: FN[R] 2VB[1V] MM; Modèle Grille: Grille [R] BR[V]
IFC_Pset_Géométrie_Allège - Hauteur: 0 cm; Stratigraphie: ...; Épaisseur: 0 cm
IFC_Pset_Géométrie_Ébrasement - Présent: no; Côté supérieur: no; Côté INFÉRIEUR: no; Épaisseur extérieure: 0 cm; Épaisseur latérale gauche: 0 cm; Épaisseur latérale droite: 0 cm; Épiasseur latérale supérieure: 0 cm; Épaisseur diagonale gauche: 0 cm; Épaisseur diagonale droite: 0 cm; Épaisseur diagonale inférieure: 0 cm; Épaisseur diagonale supérieure: 0 cm; Épaisseur intérieur: 0 cm
IFC_Pset_Géométrie_Seuil - Type: Aucun; Épaisseur: 0 cm; Épaisseur interne: 0 cm; Décalage séparation: 0 cm; Appui extérieur: 0 cm; Appui intérieur: 0 cm; Côté latéral externe: 0 cm; Côté latéral interne: 0 cm
IFC_Pset_Géométrie_Chambranle - Position: Aucun; Épaisseur Chambranle intérieur: 0 cm; Longueur Chambranle intérieur: 0 cm; Superposition Chambranle intérieur: 0 cm; Épaisseur Intrados: 0 cm; Épaisseur Chambranle extérieur: 0 cm; Largeur Chambranle extérieur: 0 cm; Superposition Chambranle extérieur: 0 cm; Épaisseur Intrados extérieur: 0 cm
IFC_Pset_Géométrie_CORNICHE depuis profil - Position: Aucune; sets with these values: 2
IFC_Pset_Géométrie_CORNICHE Extérieure à partir d'un profil - Décalage: 0; Angle: 0 deg; Symétrie: no; Fermer: no; sets with these values: 2
IFC_Pset_Géométrie_BASE Extérieure à partir d'un profil - Angle: 0 deg; Symétrie: no; Côté: 0 cm; sets with these values: 2
IFC_Pset_Géométrie_1° MENUISERIE - Position: Intérieur; Décalage: 12 cm
IFC_Pset_Géométrie_2° MENUISERIE - Décalage: 0 cm
IFC_Pset_Géométrie - Côté extérieur: 1; Invertir (dte/gche): no; Invertir (intérieur/extérieur): no; Largeur: 90.4607 cm; Hauteur: 70.7252 cm; Hauteur 2: 0 cm; Rayon Arc: 0 cm; Rayon Cercle: 0 cm; Demi-axe horizontal: 0 cm; Demi-axe vertical: 0 cm
IFC_Pset_Géométrie_GRILLE - Position: Extérieur; décalage: 8 cm; Offset latéral: 0 cm; Décalage supérieur: 0 cm; Décalage inférieur: 0 cm; Nombre accrochages latéraux: 0; Nombre d'accrochages supérieurs: 0; Nombre accrochages inférieurs: 0
IFC_Pset_Système de Référence Altimétrique_INFÉRIEUR - NIVEAU: Rez-de-Jardin (Rez-de-Jardin 15545); delta: 188.808 cm; sous Niveau: <aucun>
IFC_Pset_Données Métré - Surface 1re Menuiserie: 6400 cm2; Surface Vitre 1re Menuiserie: 2500 cm2; Surface du Cadre de la 1re Menuiserie: 3900 cm2; Surface 2e Menuiserie: 0 cm2; Surface Vitre 2e Menuiserie: 0 cm2; Surface du Cadre de la 2ème Menuiserie: 0 cm2; Surface de l'Ouverture: 6400 cm2; Surface de l'Ébrasement: 0 cm2; Surface du Seuil: 0 cm2; Surface du Seuil intérieur: 0 cm2; Volume du seuil: 0 cm3; Volume du seuil intérieur: 0 cm3; Surface de la Grille: 6400 cm2; Volume de la Grille: 0 cm3
IFC_Pset_Matériaux_1° MENUISERIE - Cadre externe: Blanc trafic; Verre: Transparent; Poignée: Aluminium satiné
IFC_Pset_Matériaux_GRILLE - Cadre externe: Blanc de sécurité; Grillage: Blanc de sécurité
Pset_WindowCommon - Reference: FN[R] 2VB[1V] MM (..\Menuiserie classique\Fenêtre et Balcon\) <aucun>

# IfcWindow: FN[R] 2VB[1V] MM (2)
In: Niveau 2
Type - OperationType: DOUBLE_PANEL_VERTICAL; ParameterTakesPrecedence: yes; Sizeable: no; Material: Transparent, Bleu france, Aluminium satiné
Type - IfcWindowLiningProperties - LiningDepth: 8 cm; LiningThickness: 5 cm; MullionThickness: 0.1 cm; FirstMullionOffset: 0.5
Type - IfcWindowPanelProperties - OperationType: SIDEHUNGLEFTHAND; PanelPosition: LEFT; FrameDepth: 7 cm; FrameThickness: 5 cm
Description: Fenêtre
__RECOGNIZE__ - TPLG: 101; TPLG_OD: 9004; GENERATE: 1
CTLG_EXTERNAL_LINK - 0, DocType: 3; 0, Tag: 100; 0, Crc: -1547682682; 1, DocType: 2; 1, Tag: 0; 1, Crc: -746779066; 2, DocType: 2; 2, Tag: 102; 2, Crc: 1181025438; 3, DocType: 2; 3, Tag: 104; 3, Crc: -623492449; 4, DocType: 2; 4, Tag: 107; 4, Crc: 1305662025
IFC_PSET_PolygonOffset - polygonOffsetFactor: 2; polygonOffsetUnits: 2
IFC_Pset_Caractéristiques - Numéro niveau: 05; Titre niveau: Niveau 2; Modèle 1re menuiserie: FN[R] 2VB[1V] MM
IFC_Pset_Géométrie_Allège - Hauteur: 0 cm; Stratigraphie: ...; Épaisseur: 0 cm
IFC_Pset_Géométrie_Ébrasement - Présent: no; Côté supérieur: no; Côté INFÉRIEUR: no; Épaisseur extérieure: 0 cm; Épaisseur latérale gauche: 0 cm; Épaisseur latérale droite: 0 cm; Épiasseur latérale supérieure: 0 cm; Épaisseur diagonale gauche: 0 cm; Épaisseur diagonale droite: 0 cm; Épaisseur diagonale inférieure: 0 cm; Épaisseur diagonale supérieure: 0 cm; Épaisseur intérieur: 0 cm
IFC_Pset_Géométrie_Seuil - Type: Aucun; Épaisseur: 0 cm; Épaisseur interne: 0 cm; Décalage séparation: 0 cm; Appui extérieur: 0 cm; Appui intérieur: 0 cm; Côté latéral externe: 0 cm; Côté latéral interne: 0 cm
IFC_Pset_Géométrie_Chambranle - Position: Aucun; Épaisseur Chambranle intérieur: 0 cm; Longueur Chambranle intérieur: 0 cm; Superposition Chambranle intérieur: 0 cm; Épaisseur Intrados: 0 cm; Épaisseur Chambranle extérieur: 0 cm; Largeur Chambranle extérieur: 0 cm; Superposition Chambranle extérieur: 0 cm; Épaisseur Intrados extérieur: 0 cm
IFC_Pset_Géométrie_CORNICHE depuis profil - Position: Aucune; sets with these values: 2
IFC_Pset_Géométrie_CORNICHE Extérieure à partir d'un profil - Décalage: 0; Angle: 0 deg; Symétrie: no; Fermer: no; sets with these values: 2
IFC_Pset_Géométrie_BASE Extérieure à partir d'un profil - Angle: 0 deg; Symétrie: no; Côté: 0 cm; sets with these values: 2
IFC_Pset_Géométrie_1° MENUISERIE - Position: Extérieur; Décalage: 0 cm
IFC_Pset_Géométrie_2° MENUISERIE - Décalage: 0 cm
IFC_Pset_Géométrie - Invertir (dte/gche): no; Hauteur 2: 0 cm; Rayon Arc: 0 cm; Rayon Cercle: 0 cm; Demi-axe horizontal: 0 cm; Demi-axe vertical: 0 cm
IFC_Pset_Géométrie_GRILLE - décalage: 0 cm; Offset latéral: 0 cm; Décalage supérieur: 0 cm; Décalage inférieur: 0 cm; Nombre accrochages latéraux: 0; Nombre d'accrochages supérieurs: 0; Nombre accrochages inférieurs: 0
IFC_Pset_Système de Référence Altimétrique_INFÉRIEUR - NIVEAU: Niveau 2 (Niveau 2 13545); sous Niveau: <aucun>
IFC_Pset_Données Métré - Surface 2e Menuiserie: 0 cm2; Surface Vitre 2e Menuiserie: 0 cm2; Surface du Cadre de la 2ème Menuiserie: 0 cm2; Surface de l'Ébrasement: 0 cm2; Surface du Seuil: 0 cm2; Surface du Seuil intérieur: 0 cm2; Volume du seuil: 0 cm3; Volume du seuil intérieur: 0 cm3; Surface de la Grille: 0 cm2; Volume de la Grille: 0 cm3
IFC_Pset_Matériaux_1° MENUISERIE - Cadre externe: Bleu france; Verre: Transparent; Poignée: Aluminium satiné
Pset_WindowCommon - Reference: FN[R] 2VB[1V] MM (..\Menuiserie classique\Fenêtre et Balcon\) <aucun>
Name | OverallHeight (cm) = Hauteur (cm) | OverallWidth (cm) = Largeur (cm) | __RECOGNIZE__, ID = IFC_Pset_Caractéristiques, ID | Numérotation | Côté extérieur | Invertir (intérieur/extérieur) | delta (cm) | Surface 1re Menuiserie (cm2) = Surface de l'Ouverture (cm2) | Surface Vitre 1re Menuiserie (cm2) | Surface du Cadre de la 1re Menuiserie (cm2)
Fenêtre 162063 | 151 | 103 | 162063 | 061 | 1 | yes | 54 | 15600 | 8300 | 7300
Fenêtre 159512 | 155 | 102.786 | 159512 | 060 | 0 | no | 52 | 15900 | 8500 | 7400

# IfcWindow: FN[R] 2VB[1V] MM (2)
In: Niveau 2
Type - OperationType: DOUBLE_PANEL_VERTICAL; ParameterTakesPrecedence: yes; Sizeable: no; Material: Transparent, Bleu france, Brèche oniciata, Aluminium satiné
Type - IfcWindowLiningProperties - LiningDepth: 8 cm; LiningThickness: 5 cm; MullionThickness: 0.1 cm; FirstMullionOffset: 0.5
Type - IfcWindowPanelProperties - OperationType: SIDEHUNGLEFTHAND; PanelPosition: LEFT; FrameDepth: 7 cm; FrameThickness: 5 cm
Description: Fenêtre; OverallWidth: 102.648 cm
__RECOGNIZE__ - TPLG: 101; TPLG_OD: 9004; GENERATE: 1
CTLG_EXTERNAL_LINK - 0, DocType: 3; 0, Tag: 100; 0, Crc: -1547682682; 1, DocType: 2; 1, Tag: 0; 1, Crc: -746779066; 2, DocType: 2; 2, Tag: 15; 2, Crc: 1141262141; 3, DocType: 2; 3, Tag: 102; 3, Crc: 1181025438; 4, DocType: 2; 4, Tag: 104; 4, Crc: -623492449; 5, DocType: 2; 5, Tag: 107; 5, Crc: 1305662025
IFC_PSET_PolygonOffset - polygonOffsetFactor: 2; polygonOffsetUnits: 2
IFC_Pset_Caractéristiques - Numéro niveau: 05; Titre niveau: Niveau 2; Modèle 1re menuiserie: FN[R] 2VB[1V] MM
IFC_Pset_Géométrie_Allège - Hauteur: 0 cm; Stratigraphie: ...; Épaisseur: 0 cm
IFC_Pset_Géométrie_Ébrasement - Présent: no; Côté supérieur: no; Côté INFÉRIEUR: no; Épaisseur extérieure: 0 cm; Épaisseur latérale gauche: 0 cm; Épaisseur latérale droite: 0 cm; Épiasseur latérale supérieure: 0 cm; Épaisseur diagonale gauche: 0 cm; Épaisseur diagonale droite: 0 cm; Épaisseur diagonale inférieure: 0 cm; Épaisseur diagonale supérieure: 0 cm; Épaisseur intérieur: 0 cm
IFC_Pset_Géométrie_Seuil - Type: Unique; Épaisseur: 3 cm; Épaisseur interne: 3 cm; Décalage séparation: 0 cm; Appui extérieur: 0 cm; Appui intérieur: 11 cm; Côté latéral externe: 0 cm; Côté latéral interne: 0 cm
IFC_Pset_Géométrie_Chambranle - Position: Aucun; Épaisseur Chambranle intérieur: 0 cm; Longueur Chambranle intérieur: 0 cm; Superposition Chambranle intérieur: 0 cm; Épaisseur Intrados: 0 cm; Épaisseur Chambranle extérieur: 0 cm; Largeur Chambranle extérieur: 0 cm; Superposition Chambranle extérieur: 0 cm; Épaisseur Intrados extérieur: 0 cm
IFC_Pset_Géométrie_CORNICHE depuis profil - Position: Aucune; sets with these values: 2
IFC_Pset_Géométrie_CORNICHE Extérieure à partir d'un profil - Décalage: 0; Angle: 0 deg; Symétrie: no; Fermer: no; sets with these values: 2
IFC_Pset_Géométrie_BASE Extérieure à partir d'un profil - Angle: 0 deg; Symétrie: no; Côté: 0 cm; sets with these values: 2
IFC_Pset_Géométrie_1° MENUISERIE - Position: Extérieur; Décalage: 0 cm
IFC_Pset_Géométrie_2° MENUISERIE - Décalage: 0 cm
IFC_Pset_Géométrie - Côté extérieur: 0; Invertir (dte/gche): no; Invertir (intérieur/extérieur): no; Largeur: 102.648 cm; Hauteur 2: 0 cm; Rayon Arc: 0 cm; Rayon Cercle: 0 cm; Demi-axe horizontal: 0 cm; Demi-axe vertical: 0 cm
IFC_Pset_Géométrie_GRILLE - décalage: 0 cm; Offset latéral: 0 cm; Décalage supérieur: 0 cm; Décalage inférieur: 0 cm; Nombre accrochages latéraux: 0; Nombre d'accrochages supérieurs: 0; Nombre accrochages inférieurs: 0
IFC_Pset_Système de Référence Altimétrique_INFÉRIEUR - NIVEAU: Niveau 2 (Niveau 2 13545); sous Niveau: <aucun>
IFC_Pset_Données Métré - Surface 2e Menuiserie: 0 cm2; Surface Vitre 2e Menuiserie: 0 cm2; Surface du Cadre de la 2ème Menuiserie: 0 cm2; Surface de l'Ébrasement: 0 cm2; Surface du Seuil: 2000 cm2; Surface du Seuil intérieur: 0 cm2; Volume du seuil: 10000 cm3; Volume du seuil intérieur: 10000 cm3; Surface de la Grille: 0 cm2; Volume de la Grille: 0 cm3
IFC_Pset_Matériaux - Seuil: Brèche oniciata
IFC_Pset_Matériaux_1° MENUISERIE - Cadre externe: Bleu france; Verre: Transparent; Poignée: Aluminium satiné
Pset_WindowCommon - Reference: FN[R] 2VB[1V] MM (..\Menuiserie classique\Fenêtre et Balcon\) <aucun>
Name | OverallHeight (cm) = Hauteur (cm) | __RECOGNIZE__, ID = IFC_Pset_Caractéristiques, ID | Numérotation | delta (cm) | Surface 1re Menuiserie (cm2) = Surface de l'Ouverture (cm2) | Surface Vitre 1re Menuiserie (cm2) | Surface du Cadre de la 1re Menuiserie (cm2)
Fenêtre 173266 | 165 | 173266 | 068 | 59 | 16900 | 9100 | 7800
Fenêtre 171997 | 153 | 171997 | 067 | 54 | 15700 | 8300 | 7400

# IfcWindow: FN[R] 2VB[1V] MM (6)
In: Niveau 2
Type - OperationType: DOUBLE_PANEL_VERTICAL; ParameterTakesPrecedence: yes; Sizeable: no; Material: Transparent, Jaune 255-255-0, Aluminium satiné
Type - IfcWindowLiningProperties - LiningDepth: 8 cm; LiningThickness: 5 cm; MullionThickness: 0.1 cm; FirstMullionOffset: 0.5
Type - IfcWindowPanelProperties - OperationType: SIDEHUNGLEFTHAND; PanelPosition: LEFT; FrameDepth: 7 cm; FrameThickness: 5 cm
Description: Fenêtre
__RECOGNIZE__ - TPLG: 101; TPLG_OD: 9004; GENERATE: 1
CTLG_EXTERNAL_LINK - 0, DocType: 3; 0, Tag: 100; 0, Crc: -1547682682; 1, DocType: 2; 1, Tag: 0; 1, Crc: -746779066; 2, DocType: 2; 2, Tag: 102; 2, Crc: -799740758; 3, DocType: 2; 3, Tag: 104; 3, Crc: -623492449; 4, DocType: 2; 4, Tag: 107; 4, Crc: 1305662025
IFC_PSET_PolygonOffset - polygonOffsetFactor: 2; polygonOffsetUnits: 2
IFC_Pset_Caractéristiques - Numéro niveau: 05; Titre niveau: Niveau 2; Modèle 1re menuiserie: FN[R] 2VB[1V] MM
IFC_Pset_Géométrie_Allège - Hauteur: 0 cm; Stratigraphie: ...; Épaisseur: 0 cm
IFC_Pset_Géométrie_Ébrasement - Présent: no; Côté supérieur: no; Côté INFÉRIEUR: no; Épaisseur extérieure: 0 cm; Épaisseur latérale gauche: 0 cm; Épaisseur latérale droite: 0 cm; Épiasseur latérale supérieure: 0 cm; Épaisseur diagonale gauche: 0 cm; Épaisseur diagonale droite: 0 cm; Épaisseur diagonale inférieure: 0 cm; Épaisseur diagonale supérieure: 0 cm; Épaisseur intérieur: 0 cm
IFC_Pset_Géométrie_Seuil - Type: Aucun; Épaisseur: 0 cm; Épaisseur interne: 0 cm; Décalage séparation: 0 cm; Appui extérieur: 0 cm; Appui intérieur: 0 cm; Côté latéral externe: 0 cm; Côté latéral interne: 0 cm
IFC_Pset_Géométrie_Chambranle - Position: Aucun; Épaisseur Chambranle intérieur: 0 cm; Longueur Chambranle intérieur: 0 cm; Superposition Chambranle intérieur: 0 cm; Épaisseur Intrados: 0 cm; Épaisseur Chambranle extérieur: 0 cm; Largeur Chambranle extérieur: 0 cm; Superposition Chambranle extérieur: 0 cm; Épaisseur Intrados extérieur: 0 cm
IFC_Pset_Géométrie_CORNICHE depuis profil - Position: Aucune; sets with these values: 2
IFC_Pset_Géométrie_CORNICHE Extérieure à partir d'un profil - Décalage: 0; Angle: 0 deg; Symétrie: no; Fermer: no; sets with these values: 2
IFC_Pset_Géométrie_BASE Extérieure à partir d'un profil - Angle: 0 deg; Symétrie: no; Côté: 0 cm; sets with these values: 2
IFC_Pset_Géométrie_1° MENUISERIE - Position: Extérieur
IFC_Pset_Géométrie_2° MENUISERIE - Décalage: 0 cm
IFC_Pset_Géométrie - Invertir (dte/gche): no; Hauteur 2: 0 cm; Rayon Arc: 0 cm; Rayon Cercle: 0 cm; Demi-axe horizontal: 0 cm; Demi-axe vertical: 0 cm
IFC_Pset_Géométrie_GRILLE - décalage: 0 cm; Offset latéral: 0 cm; Décalage supérieur: 0 cm; Décalage inférieur: 0 cm; Nombre accrochages latéraux: 0; Nombre d'accrochages supérieurs: 0; Nombre accrochages inférieurs: 0
IFC_Pset_Système de Référence Altimétrique_INFÉRIEUR - NIVEAU: Niveau 2 (Niveau 2 13545); sous Niveau: <aucun>
IFC_Pset_Données Métré - Surface 2e Menuiserie: 0 cm2; Surface Vitre 2e Menuiserie: 0 cm2; Surface du Cadre de la 2ème Menuiserie: 0 cm2; Surface de l'Ébrasement: 0 cm2; Surface du Seuil: 0 cm2; Surface du Seuil intérieur: 0 cm2; Volume du seuil: 0 cm3; Volume du seuil intérieur: 0 cm3; Surface de la Grille: 0 cm2; Volume de la Grille: 0 cm3
IFC_Pset_Matériaux_1° MENUISERIE - Cadre externe: Jaune 255-255-0; Verre: Transparent; Poignée: Aluminium satiné
Pset_WindowCommon - Reference: FN[R] 2VB[1V] MM (..\Menuiserie classique\Fenêtre et Balcon\) <aucun>
Name | OverallHeight (cm) = Hauteur (cm) | OverallWidth (cm) = Largeur (cm) | __RECOGNIZE__, ID = IFC_Pset_Caractéristiques, ID | Numérotation | Décalage (cm) | Côté extérieur | Invertir (intérieur/extérieur) | delta (cm) | Surface 1re Menuiserie (cm2) = Surface de l'Ouverture (cm2) | Surface Vitre 1re Menuiserie (cm2) | Surface du Cadre de la 1re Menuiserie (cm2)
Fenêtre 152974 | 155.6 | 103.26 | 152974 | 055 | 3 | 1 | no | 52 | 16100 | 8600 | 7500
Fenêtre 152973 | 155.601 | 102.583 | 152973 | 054 | 0 | 1 | no | 52 | 16000 | 8500 | 7500
Fenêtre 158942 | 100 | 108.764 | 158942 | 059 | -4 | 0 | no | 95 | 10900 | 5400 | 5500
Fenêtre 158880 | 100 | 107.315 | 158880 | 056 | -2 | 1 | yes | 95.5 | 10700 | 5300 | 5500
Fenêtre 158930 | 130 | 103.163 | 158930 | 058 | 0 | 1 | yes | 92.2965 | 13400 | 6900 | 6500
Fenêtre 158881 | 125 | 103.163 | 158881 | 057 | -4 | 1 | yes | 92.3 | 12900 | 6600 | 6300

# IfcWindow: FN[R] 2VB[1V] MM (4)
In: Niveau 2
Type - OperationType: DOUBLE_PANEL_VERTICAL; ParameterTakesPrecedence: yes; Sizeable: no; Material: Transparent, Jaune 255-255-0, Brèche oniciata, Aluminium satiné
Type - IfcWindowLiningProperties - LiningDepth: 8 cm; LiningThickness: 5 cm; MullionThickness: 0.1 cm; FirstMullionOffset: 0.5
Type - IfcWindowPanelProperties - OperationType: SIDEHUNGLEFTHAND; PanelPosition: LEFT; FrameDepth: 7 cm; FrameThickness: 5 cm
Description: Fenêtre
__RECOGNIZE__ - TPLG: 101; TPLG_OD: 9004; GENERATE: 1
CTLG_EXTERNAL_LINK - 0, DocType: 3; 0, Tag: 100; 0, Crc: -1547682682; 1, DocType: 2; 1, Tag: 0; 1, Crc: -746779066; 2, DocType: 2; 2, Tag: 15; 2, Crc: 1141262141; 3, DocType: 2; 3, Tag: 102; 3, Crc: -799740758; 4, DocType: 2; 4, Tag: 104; 4, Crc: -623492449; 5, DocType: 2; 5, Tag: 107; 5, Crc: 1305662025
IFC_PSET_PolygonOffset - polygonOffsetFactor: 2; polygonOffsetUnits: 2
IFC_Pset_Caractéristiques - Numéro niveau: 05; Titre niveau: Niveau 2; Modèle 1re menuiserie: FN[R] 2VB[1V] MM
IFC_Pset_Géométrie_Allège - Hauteur: 0 cm; Stratigraphie: ...; Épaisseur: 0 cm
IFC_Pset_Géométrie_Ébrasement - Présent: no; Côté supérieur: no; Côté INFÉRIEUR: no; Épaisseur extérieure: 0 cm; Épaisseur latérale gauche: 0 cm; Épaisseur latérale droite: 0 cm; Épiasseur latérale supérieure: 0 cm; Épaisseur diagonale gauche: 0 cm; Épaisseur diagonale droite: 0 cm; Épaisseur diagonale inférieure: 0 cm; Épaisseur diagonale supérieure: 0 cm; Épaisseur intérieur: 0 cm
IFC_Pset_Géométrie_Seuil - Type: Unique; Épaisseur: 3 cm; Épaisseur interne: 3 cm; Décalage séparation: 0 cm; Appui extérieur: 0 cm; Côté latéral externe: 0 cm; Côté latéral interne: 0 cm
IFC_Pset_Géométrie_Chambranle - Position: Aucun; Épaisseur Chambranle intérieur: 0 cm; Longueur Chambranle intérieur: 0 cm; Superposition Chambranle intérieur: 0 cm; Épaisseur Intrados: 0 cm; Épaisseur Chambranle extérieur: 0 cm; Largeur Chambranle extérieur: 0 cm; Superposition Chambranle extérieur: 0 cm; Épaisseur Intrados extérieur: 0 cm
IFC_Pset_Géométrie_CORNICHE depuis profil - Position: Aucune; sets with these values: 2
IFC_Pset_Géométrie_CORNICHE Extérieure à partir d'un profil - Décalage: 0; Angle: 0 deg; Symétrie: no; Fermer: no; sets with these values: 2
IFC_Pset_Géométrie_BASE Extérieure à partir d'un profil - Angle: 0 deg; Symétrie: no; Côté: 0 cm; sets with these values: 2
IFC_Pset_Géométrie_1° MENUISERIE - Position: Extérieur; Décalage: 0 cm
IFC_Pset_Géométrie_2° MENUISERIE - Décalage: 0 cm
IFC_Pset_Géométrie - Invertir (intérieur/extérieur): no; Hauteur 2: 0 cm; Rayon Arc: 0 cm; Rayon Cercle: 0 cm; Demi-axe horizontal: 0 cm; Demi-axe vertical: 0 cm
IFC_Pset_Géométrie_GRILLE - décalage: 0 cm; Offset latéral: 0 cm; Décalage supérieur: 0 cm; Décalage inférieur: 0 cm; Nombre accrochages latéraux: 0; Nombre d'accrochages supérieurs: 0; Nombre accrochages inférieurs: 0
IFC_Pset_Système de Référence Altimétrique_INFÉRIEUR - NIVEAU: Niveau 2 (Niveau 2 13545); sous Niveau: <aucun>
IFC_Pset_Données Métré - Surface 2e Menuiserie: 0 cm2; Surface Vitre 2e Menuiserie: 0 cm2; Surface du Cadre de la 2ème Menuiserie: 0 cm2; Surface de l'Ébrasement: 0 cm2; Surface du Seuil intérieur: 0 cm2; Surface de la Grille: 0 cm2; Volume de la Grille: 0 cm3
IFC_Pset_Matériaux - Seuil: Brèche oniciata
IFC_Pset_Matériaux_1° MENUISERIE - Cadre externe: Jaune 255-255-0; Verre: Transparent; Poignée: Aluminium satiné
Pset_WindowCommon - Reference: FN[R] 2VB[1V] MM (..\Menuiserie classique\Fenêtre et Balcon\) <aucun>
Name | OverallHeight (cm) = Hauteur (cm) | OverallWidth (cm) = Largeur (cm) | __RECOGNIZE__, ID = IFC_Pset_Caractéristiques, ID | Numérotation | Appui intérieur (cm) | Côté extérieur | Invertir (dte/gche) | delta (cm) | Surface 1re Menuiserie (cm2) = Surface de l'Ouverture (cm2) | Surface Vitre 1re Menuiserie (cm2) | Surface du Cadre de la 1re Menuiserie (cm2) | Surface du Seuil (cm2) | Volume du seuil (cm3) = Volume du seuil intérieur (cm3)
Fenêtre 178609 | 170 | 100.092 | 178609 | 071 | 11 | 0 | yes | 58 | 17000 | 9100 | 8000 | 2000 | 10000
Fenêtre 178841 | 170 | 100.84 | 178841 | 072 | 11 | 0 | yes | 55 | 17100 | 9200 | 8000 | 2000 | 10000
Fenêtre 180595 | 156 | 101.9 | 180595 | 073 | 11 | 1 | yes | 52 | 15900 | 8400 | 7500 | 2100 | 10000
Fenêtre 163845 | 113 | 106.335 | 163845 | 062 | 2 | 0 | no | 55 | 12000 | 6100 | 5900 | 1100 | 0

# IfcWindow: FN[R] 2VB[1V] MM (4)
Type - ParameterTakesPrecedence: no; Sizeable: no; Material: Transparent, Blanc trafic, Aluminium satiné
Type - IfcWindowLiningProperties - LiningDepth: 8 cm; LiningThickness: 5 cm
Type - IfcWindowPanelProperties - OperationType: FIXEDCASEMENT; FrameDepth: 0 cm; FrameThickness: 0 cm
Description: Fenêtre
__RECOGNIZE__ - TPLG: 101; TPLG_OD: 9004; GENERATE: 1
CTLG_EXTERNAL_LINK - 0, DocType: 3; 0, Tag: 100; 0, Crc: -403746283; 1, DocType: 2; 1, Tag: 0; 1, Crc: -746779066; 2, DocType: 2; 2, Tag: 102; 2, Crc: -848491367; 3, DocType: 2; 3, Tag: 104; 3, Crc: -623492449; 4, DocType: 2; 4, Tag: 107; 4, Crc: -212966465
IFC_PSET_PolygonOffset - polygonOffsetFactor: 2; polygonOffsetUnits: 2
IFC_Pset_Caractéristiques - Modèle 1re menuiserie: FN[R] 2VB[1V] MM
IFC_Pset_Géométrie_Allège - Hauteur: 0 cm; Stratigraphie: ...; Épaisseur: 0 cm
IFC_Pset_Géométrie_Ébrasement - Côté supérieur: no; Côté INFÉRIEUR: no; Épaisseur intérieur: 0 cm
IFC_Pset_Géométrie_Seuil - Type: Aucun; Épaisseur: 0 cm; Épaisseur interne: 0 cm; Décalage séparation: 0 cm; Appui extérieur: 0 cm; Appui intérieur: 0 cm; Côté latéral externe: 0 cm; Côté latéral interne: 0 cm
IFC_Pset_Géométrie_Chambranle - Position: Aucun; Épaisseur Chambranle intérieur: 0 cm; Longueur Chambranle intérieur: 0 cm; Superposition Chambranle intérieur: 0 cm; Épaisseur Intrados: 0 cm; Épaisseur Chambranle extérieur: 0 cm; Largeur Chambranle extérieur: 0 cm; Superposition Chambranle extérieur: 0 cm; Épaisseur Intrados extérieur: 0 cm
IFC_Pset_Géométrie_CORNICHE depuis profil - Position: Aucune; sets with these values: 2
IFC_Pset_Géométrie_CORNICHE Extérieure à partir d'un profil - Décalage: 0; Angle: 0 deg; Symétrie: no; Fermer: no; sets with these values: 2
IFC_Pset_Géométrie_BASE Extérieure à partir d'un profil - Angle: 0 deg; Symétrie: no; Côté: 0 cm; sets with these values: 2
IFC_Pset_Géométrie_1° MENUISERIE - Position: Extérieur; Décalage: 0 cm
IFC_Pset_Géométrie_2° MENUISERIE - Décalage: 0 cm
IFC_Pset_Géométrie - Invertir (dte/gche): no; Invertir (intérieur/extérieur): no; Hauteur 2: 0 cm; Rayon Arc: 0 cm; Rayon Cercle: 0 cm; Demi-axe horizontal: 0 cm; Demi-axe vertical: 0 cm
IFC_Pset_Géométrie_GRILLE - décalage: 0 cm; Offset latéral: 0 cm; Décalage supérieur: 0 cm; Décalage inférieur: 0 cm; Nombre accrochages latéraux: 0; Nombre d'accrochages supérieurs: 0; Nombre accrochages inférieurs: 0
IFC_Pset_Système de Référence Altimétrique_INFÉRIEUR - sous Niveau: <aucun>
IFC_Pset_Données Métré - Surface 2e Menuiserie: 0 cm2; Surface Vitre 2e Menuiserie: 0 cm2; Surface du Cadre de la 2ème Menuiserie: 0 cm2; Surface du Seuil: 0 cm2; Surface du Seuil intérieur: 0 cm2; Volume du seuil: 0 cm3; Volume du seuil intérieur: 0 cm3; Surface de la Grille: 0 cm2; Volume de la Grille: 0 cm3
IFC_Pset_Matériaux_1° MENUISERIE - Cadre externe: Blanc trafic; Verre: Transparent; Poignée: Aluminium satiné
Pset_WindowCommon - Reference: FN[R] 2VB[1V] MM (..\Menuiserie classique\Fenêtre et Balcon\) <aucun>
Name | In | OverallHeight (cm) = Hauteur (cm) | OverallWidth (cm) = Largeur (cm) | __RECOGNIZE__, ID = IFC_Pset_Caractéristiques, ID | Numérotation | Numéro niveau | Titre niveau | Présent | Épaisseur extérieure (cm) | Épaisseur latérale gauche (cm) = Épaisseur latérale droite (cm) = Épiasseur latérale supérieure (cm) | Épaisseur diagonale gauche (cm) = Épaisseur diagonale inférieure (cm) = Épaisseur diagonale supérieure (cm) | Épaisseur diagonale droite (cm) | Côté extérieur | NIVEAU | delta (cm) | Surface 1re Menuiserie (cm2) = Surface de l'Ouverture (cm2) | Surface Vitre 1re Menuiserie (cm2) | Surface du Cadre de la 1re Menuiserie (cm2) | Surface de l'Ébrasement (cm2) | Données
Fenêtre 78024 | Rez-de-Jardin | 69 | 94.0556 | 78024 | 026 | 02 | Rez-de-Jardin | no | 0 | 0 | 0 | 0 | 0 | Rez-de-Jardin (Rez-de-Jardin 15545) | 155 | 6500 | 1600 | 4900 | 0
Fenêtre 132701 | Niveau 1 | 215 | 104.343 | 132701 | 052 | 04 | Niveau 1 | yes | 6 | 2 | 2.5 | 3 | 0 | Niveau 1 (Niveau 1 2343) | 53 | 22400 | 9700 | 12800 | 18100 | [a : 60,00; b: 20,00; c: 25,00; d: 0,00] mm
Fenêtre 132699 | Niveau 1 | 215 | 104.767 | 132699 | 050 | 04 | Niveau 1 | yes | 6 | 2 | 2.5 | 3 | 1 | Niveau 1 (Niveau 1 2343) | 53 | 22500 | 9700 | 12800 | 18100 | [a : 60,00; b: 20,00; c: 25,00; d: 0,00] mm
Fenêtre 132700 | Niveau 1 | 150 | 101.901 | 132700 | 051 | 04 | Niveau 1 | yes | 6 | 2 | 2.5 | 3 | 1 | Niveau 1 (Niveau 1 2343) | 51 | 15300 | 6000 | 9300 | 12600 | [a : 60,00; b: 20,00; c: 25,00; d: 0,00] mm

# IfcWindow: FN[R] 2VB[1V] MM, Fenêtre 132694
In: Niveau 1
Type - ParameterTakesPrecedence: no; Sizeable: no; Material: Transparent, Brèche oniciata, Blanc trafic, Aluminium satiné
Type - IfcWindowLiningProperties - LiningDepth: 8 cm; LiningThickness: 5 cm
Type - IfcWindowPanelProperties - OperationType: FIXEDCASEMENT; FrameDepth: 0 cm; FrameThickness: 0 cm
Description: Fenêtre; OverallHeight: 146.46 cm; OverallWidth: 89.9259 cm
__RECOGNIZE__ - ID: 132694; TPLG: 101; TPLG_OD: 9004; GENERATE: 1
CTLG_EXTERNAL_LINK - 0, DocType: 3; 0, Tag: 100; 0, Crc: -403746283; 1, DocType: 2; 1, Tag: 0; 1, Crc: -746779066; 2, DocType: 2; 2, Tag: 15; 2, Crc: 1141262141; 3, DocType: 2; 3, Tag: 102; 3, Crc: -848491367; 4, DocType: 2; 4, Tag: 104; 4, Crc: -623492449; 5, DocType: 2; 5, Tag: 107; 5, Crc: -212966465
IFC_PSET_PolygonOffset - polygonOffsetFactor: 2; polygonOffsetUnits: 2
IFC_Pset_Caractéristiques - ID: 132694; Numérotation: 049; Numéro niveau: 04; Titre niveau: Niveau 1; Modèle 1re menuiserie: FN[R] 2VB[1V] MM
IFC_Pset_Géométrie_Allège - Hauteur: 0 cm; Stratigraphie: ...; Épaisseur: 0 cm
IFC_Pset_Géométrie_Ébrasement - Présent: yes; Côté supérieur: yes; Côté INFÉRIEUR: no; Épaisseur extérieure: 6 cm; Épaisseur latérale gauche: 2 cm; Épaisseur latérale droite: 2 cm; Épiasseur latérale supérieure: 2 cm; Épaisseur diagonale gauche: 2.5 cm; Épaisseur diagonale droite: 2 cm; Épaisseur diagonale inférieure: 2.5 cm; Épaisseur diagonale supérieure: 1.5 cm; Épaisseur intérieur: 0 cm; Données: [a : 60,00; b: 20,00; c: 25,00; d: 0,00] mm
IFC_Pset_Géométrie_Seuil - Type: Unique; Épaisseur: 3 cm; Épaisseur interne: 3 cm; Décalage séparation: 0 cm; Appui extérieur: 0 cm; Appui intérieur: 5 cm; Côté latéral externe: 5 cm; Côté latéral interne: 5 cm
IFC_Pset_Géométrie_Chambranle - Position: Aucun; Épaisseur Chambranle intérieur: 0 cm; Longueur Chambranle intérieur: 0 cm; Superposition Chambranle intérieur: 0 cm; Épaisseur Intrados: 0 cm; Épaisseur Chambranle extérieur: 0 cm; Largeur Chambranle extérieur: 0 cm; Superposition Chambranle extérieur: 0 cm; Épaisseur Intrados extérieur: 0 cm
IFC_Pset_Géométrie_CORNICHE depuis profil - Position: Aucune; sets with these values: 2
IFC_Pset_Géométrie_CORNICHE Extérieure à partir d'un profil - Décalage: 0; Angle: 0 deg; Symétrie: no; Fermer: no; sets with these values: 2
IFC_Pset_Géométrie_BASE Extérieure à partir d'un profil - Angle: 0 deg; Symétrie: no; Côté: 0 cm; sets with these values: 2
IFC_Pset_Géométrie_1° MENUISERIE - Position: Extérieur; Décalage: -3 cm
IFC_Pset_Géométrie_2° MENUISERIE - Décalage: 0 cm
IFC_Pset_Géométrie - Côté extérieur: 0; Invertir (dte/gche): no; Invertir (intérieur/extérieur): no; Largeur: 89.9259 cm; Hauteur: 146.46 cm; Hauteur 2: 0 cm; Rayon Arc: 0 cm; Rayon Cercle: 0 cm; Demi-axe horizontal: 0 cm; Demi-axe vertical: 0 cm
IFC_Pset_Géométrie_GRILLE - décalage: 0 cm; Offset latéral: 0 cm; Décalage supérieur: 0 cm; Décalage inférieur: 0 cm; Nombre accrochages latéraux: 0; Nombre d'accrochages supérieurs: 0; Nombre accrochages inférieurs: 0
IFC_Pset_Système de Référence Altimétrique_INFÉRIEUR - NIVEAU: Niveau 1 (Niveau 1 2343); delta: 145.202 cm; sous Niveau: <aucun>
IFC_Pset_Données Métré - Surface 1re Menuiserie: 13200 cm2; Surface Vitre 1re Menuiserie: 4400 cm2; Surface du Cadre de la 1re Menuiserie: 8800 cm2; Surface 2e Menuiserie: 0 cm2; Surface Vitre 2e Menuiserie: 0 cm2; Surface du Cadre de la 2ème Menuiserie: 0 cm2; Surface de l'Ouverture: 13200 cm2; Surface de l'Ébrasement: 16800 cm2; Surface du Seuil: 4400 cm2; Surface du Seuil intérieur: 0 cm2; Volume du seuil: 10000 cm3; Volume du seuil intérieur: 10000 cm3; Surface de la Grille: 0 cm2; Volume de la Grille: 0 cm3
IFC_Pset_Matériaux - Seuil: Brèche oniciata
IFC_Pset_Matériaux_1° MENUISERIE - Cadre externe: Blanc trafic; Verre: Transparent; Poignée: Aluminium satiné
Pset_WindowCommon - Reference: FN[R] 2VB[1V] MM (..\Menuiserie classique\Fenêtre et Balcon\) <aucun>

# IfcWindow: FN[R] 2VB[2V] MM, Fenêtre 23593
In: Rez-de-chaussée
Type - ParameterTakesPrecedence: no; Sizeable: no; Material: Transparent, Blanc gris, Aluminium satiné, Blanc trafic
Type - IfcWindowLiningProperties - LiningDepth: 8 cm; LiningThickness: 5 cm
Type - IfcWindowPanelProperties - OperationType: FIXEDCASEMENT; FrameDepth: 0 cm; FrameThickness: 0 cm
Description: Fenêtre; OverallHeight: 222.657 cm; OverallWidth: 133.151 cm
__RECOGNIZE__ - ID: 23593; TPLG: 101; TPLG_OD: 9004; GENERATE: 1
CTLG_EXTERNAL_LINK - 0, DocType: 3; 0, Tag: 100; 0, Crc: 1030203749; 1, DocType: 2; 1, Tag: 0; 1, Crc: -746779066; 2, DocType: 2; 2, Tag: 102; 2, Crc: 2064387956; 3, DocType: 2; 3, Tag: 104; 3, Crc: -623492449; 4, DocType: 2; 4, Tag: 105; 4, Crc: -848491367; 5, DocType: 2; 5, Tag: 107; 5, Crc: -212966465
IFC_PSET_PolygonOffset - polygonOffsetFactor: 2; polygonOffsetUnits: 2
IFC_Pset_Caractéristiques - ID: 23593; Numérotation: 001; Numéro niveau: 03; Titre niveau: Rez-de-chaussée; Modèle 1re menuiserie: FN[R] 2VB[2V] MM
IFC_Pset_Géométrie_Allège - Hauteur: 0 cm; Stratigraphie: ...; Épaisseur: 0 cm
IFC_Pset_Géométrie_Ébrasement - Présent: no; Côté supérieur: no; Côté INFÉRIEUR: no; Épaisseur extérieure: 0 cm; Épaisseur latérale gauche: 0 cm; Épaisseur latérale droite: 0 cm; Épiasseur latérale supérieure: 0 cm; Épaisseur diagonale gauche: 0 cm; Épaisseur diagonale droite: 0 cm; Épaisseur diagonale inférieure: 0 cm; Épaisseur diagonale supérieure: 0 cm; Épaisseur intérieur: 0 cm
IFC_Pset_Géométrie_Seuil - Type: Aucun; Épaisseur: 0 cm; Épaisseur interne: 0 cm; Décalage séparation: 0 cm; Appui extérieur: 0 cm; Appui intérieur: 0 cm; Côté latéral externe: 0 cm; Côté latéral interne: 0 cm
IFC_Pset_Géométrie_Chambranle - Position: Aucun; Épaisseur Chambranle intérieur: 0 cm; Longueur Chambranle intérieur: 0 cm; Superposition Chambranle intérieur: 0 cm; Épaisseur Intrados: 0 cm; Épaisseur Chambranle extérieur: 0 cm; Largeur Chambranle extérieur: 0 cm; Superposition Chambranle extérieur: 0 cm; Épaisseur Intrados extérieur: 0 cm
IFC_Pset_Géométrie_CORNICHE depuis profil - Position: Aucune; sets with these values: 2
IFC_Pset_Géométrie_CORNICHE Extérieure à partir d'un profil - Décalage: 0; Angle: 0 deg; Symétrie: no; Fermer: no; sets with these values: 2
IFC_Pset_Géométrie_BASE Extérieure à partir d'un profil - Angle: 0 deg; Symétrie: no; Côté: 0 cm; sets with these values: 2
IFC_Pset_Géométrie_1° MENUISERIE - Position: Extérieur; Décalage: 0 cm
IFC_Pset_Géométrie_2° MENUISERIE - Décalage: 0 cm
IFC_Pset_Géométrie - Côté extérieur: 1; Invertir (dte/gche): no; Invertir (intérieur/extérieur): no; Largeur: 133.151 cm; Hauteur: 222.657 cm; Hauteur 2: 0 cm; Rayon Arc: 0 cm; Rayon Cercle: 0 cm; Demi-axe horizontal: 0 cm; Demi-axe vertical: 0 cm
IFC_Pset_Géométrie_GRILLE - décalage: 0 cm; Offset latéral: 0 cm; Décalage supérieur: 0 cm; Décalage inférieur: 0 cm; Nombre accrochages latéraux: 0; Nombre d'accrochages supérieurs: 0; Nombre accrochages inférieurs: 0
IFC_Pset_Système de Référence Altimétrique_INFÉRIEUR - NIVEAU: Rez-de-chaussée (Rez-de-chaussée 1047); delta: 43.1841 cm; sous Niveau: <aucun>
IFC_Pset_Données Métré - Surface 1re Menuiserie: 29600 cm2; Surface Vitre 1re Menuiserie: 14800 cm2; Surface du Cadre de la 1re Menuiserie: 13300 cm2; Surface 2e Menuiserie: 0 cm2; Surface Vitre 2e Menuiserie: 0 cm2; Surface du Cadre de la 2ème Menuiserie: 0 cm2; Surface de l'Ouverture: 29600 cm2; Surface de l'Ébrasement: 0 cm2; Surface du Seuil: 0 cm2; Surface du Seuil intérieur: 0 cm2; Volume du seuil: 0 cm3; Volume du seuil intérieur: 0 cm3; Surface de la Grille: 0 cm2; Volume de la Grille: 0 cm3
IFC_Pset_Matériaux_1° MENUISERIE - Cadre externe: Blanc gris; Verre: Transparent; Panneau extérieur: Blanc trafic; Poignée: Aluminium satiné
Pset_WindowCommon - Reference: FN[R] 2VB[2V] MM (..\Menuiserie simple\Fenêtre et Balcon\) <aucun>

# IfcWindow: FN[R] 2VB[2V] MM (17)
Type - ParameterTakesPrecedence: no; Sizeable: no; Material: Transparent, Blanc trafic (2), Aluminium satiné
Type - IfcWindowLiningProperties - LiningDepth: 8 cm; LiningThickness: 5 cm
Type - IfcWindowPanelProperties - OperationType: FIXEDCASEMENT; FrameDepth: 0 cm; FrameThickness: 0 cm
Description: Fenêtre
__RECOGNIZE__ - TPLG: 101; TPLG_OD: 9004; GENERATE: 1
CTLG_EXTERNAL_LINK - 0, DocType: 3; 0, Tag: 100; 0, Crc: 1030203749; 1, DocType: 2; 1, Tag: 0; 1, Crc: -746779066; 2, DocType: 2; 2, Tag: 102; 2, Crc: -1897652181; 3, DocType: 2; 3, Tag: 104; 3, Crc: -623492449; 4, DocType: 2; 4, Tag: 105; 4, Crc: -848491367; 5, DocType: 2; 5, Tag: 107; 5, Crc: -212966465
IFC_PSET_PolygonOffset - polygonOffsetFactor: 2; polygonOffsetUnits: 2
IFC_Pset_Caractéristiques - Modèle 1re menuiserie: FN[R] 2VB[2V] MM
IFC_Pset_Géométrie_Allège - Hauteur: 0 cm; Stratigraphie: ...; Épaisseur: 0 cm
IFC_Pset_Géométrie_Ébrasement - Côté supérieur: no; Côté INFÉRIEUR: no; Épaisseur latérale gauche: 0 cm; Épaisseur latérale droite: 0 cm; Épiasseur latérale supérieure: 0 cm; Épaisseur intérieur: 0 cm
IFC_Pset_Géométrie_Seuil - Type: Aucun; Épaisseur: 0 cm; Épaisseur interne: 0 cm; Décalage séparation: 0 cm; Appui extérieur: 0 cm; Appui intérieur: 0 cm; Côté latéral externe: 0 cm; Côté latéral interne: 0 cm
IFC_Pset_Géométrie_Chambranle - Position: Aucun; Épaisseur Chambranle intérieur: 0 cm; Longueur Chambranle intérieur: 0 cm; Superposition Chambranle intérieur: 0 cm; Épaisseur Intrados: 0 cm; Épaisseur Chambranle extérieur: 0 cm; Largeur Chambranle extérieur: 0 cm; Superposition Chambranle extérieur: 0 cm; Épaisseur Intrados extérieur: 0 cm
IFC_Pset_Géométrie_CORNICHE depuis profil - Position: Aucune; sets with these values: 2
IFC_Pset_Géométrie_CORNICHE Extérieure à partir d'un profil - Décalage: 0; Angle: 0 deg; Symétrie: no; Fermer: no; sets with these values: 2
IFC_Pset_Géométrie_BASE Extérieure à partir d'un profil - Angle: 0 deg; Symétrie: no; Côté: 0 cm; sets with these values: 2
IFC_Pset_Géométrie_1° MENUISERIE - Position: Extérieur
IFC_Pset_Géométrie_2° MENUISERIE - Décalage: 0 cm
IFC_Pset_Géométrie - Invertir (dte/gche): no; Invertir (intérieur/extérieur): no; Hauteur 2: 0 cm; Rayon Arc: 0 cm; Rayon Cercle: 0 cm; Demi-axe horizontal: 0 cm; Demi-axe vertical: 0 cm
IFC_Pset_Géométrie_GRILLE - décalage: 0 cm; Offset latéral: 0 cm; Décalage supérieur: 0 cm; Décalage inférieur: 0 cm; Nombre accrochages latéraux: 0; Nombre d'accrochages supérieurs: 0; Nombre accrochages inférieurs: 0
IFC_Pset_Système de Référence Altimétrique_INFÉRIEUR - sous Niveau: <aucun>
IFC_Pset_Données Métré - Surface 2e Menuiserie: 0 cm2; Surface Vitre 2e Menuiserie: 0 cm2; Surface du Cadre de la 2ème Menuiserie: 0 cm2; Surface du Seuil: 0 cm2; Surface du Seuil intérieur: 0 cm2; Volume du seuil: 0 cm3; Volume du seuil intérieur: 0 cm3; Surface de la Grille: 0 cm2; Volume de la Grille: 0 cm3
IFC_Pset_Matériaux_1° MENUISERIE - Cadre externe: Blanc trafic; Verre: Transparent; Panneau extérieur: Blanc trafic; Poignée: Aluminium satiné
Pset_WindowCommon - Reference: FN[R] 2VB[2V] MM (..\Menuiserie simple\Fenêtre et Balcon\) <aucun>
Name | In | OverallHeight (cm) = Hauteur (cm) | OverallWidth (cm) = Largeur (cm) | __RECOGNIZE__, ID = IFC_Pset_Caractéristiques, ID | Numérotation | Numéro niveau | Titre niveau | Présent | Épaisseur extérieure (cm) | Épaisseur diagonale gauche (cm) = Épaisseur diagonale droite (cm) = Épaisseur diagonale inférieure (cm) = Épaisseur diagonale supérieure (cm) | Décalage (cm) | Côté extérieur | NIVEAU | delta (cm) | Surface 1re Menuiserie (cm2) = Surface de l'Ouverture (cm2) | Surface Vitre 1re Menuiserie (cm2) | Surface du Cadre de la 1re Menuiserie (cm2) | Surface de l'Ébrasement (cm2)
Fenêtre 23819 | Rez-de-chaussée | 309 | 127.567 | 23819 | 005 | 03 | Rez-de-chaussée | no | 0 | 0 | 0 | 1 | Rez-de-chaussée (Rez-de-chaussée 1047) | 54.0442 | 39400 | 20200 | 16900 | 0
Fenêtre 23822 | Rez-de-chaussée | 312 | 130.192 | 23822 | 006 | 03 | Rez-de-chaussée | no | 0 | 0 | 0 | 1 | Rez-de-chaussée (Rez-de-chaussée 1047) | 54.0442 | 40600 | 21100 | 17100 | 0
Fenêtre 23868 | Rez-de-chaussée | 316 | 104 | 23868 | 014 | 03 | Rez-de-chaussée | no | 0 | 0 | -4 | 0 | Rez-de-chaussée (Rez-de-chaussée 1047) | 50.728 | 32900 | 15000 | 16200 | 0
Fenêtre 23862 | Rez-de-chaussée | 316 | 126.688 | 23862 | 012 | 03 | Rez-de-chaussée | no | 0 | 0 | 7.5 | 0 | Rez-de-chaussée (Rez-de-chaussée 1047) | 49.8355 | 40000 | 20500 | 17100 | 0
Fenêtre 23865 | Rez-de-chaussée | 316 | 106 | 23865 | 013 | 03 | Rez-de-chaussée | no | 0 | 0 | 9 | 0 | Rez-de-chaussée (Rez-de-chaussée 1047) | 50.728 | 33500 | 15500 | 16300 | 0
Fenêtre 23844 | Rez-de-chaussée | 317 | 134.395 | 23844 | 009 | 03 | Rez-de-chaussée | no | 0 | 0 | -7 | 0 | Rez-de-chaussée (Rez-de-chaussée 1047) | 48.1145 | 42600 | 22500 | 17500 | 0
Fenêtre 23841 | Rez-de-chaussée | 317 | 118.964 | 23841 | 008 | 03 | Rez-de-chaussée | no | 0 | 0 | -7 | 0 | Rez-de-chaussée (Rez-de-chaussée 1047) | 49.1215 | 37700 | 18700 | 16900 | 0
Fenêtre 23840 | Rez-de-chaussée | 240 | 121.522 | 23840 | 007 | 03 | Rez-de-chaussée | no | 0 | 0 | 0 | 1 | Rez-de-chaussée (Rez-de-chaussée 1047) | 51.1 | 29200 | 14100 | 13600 | 0
Fenêtre 23859 | Rez-de-chaussée | 294 | 189.021 | 23859 | 011 | 03 | Rez-de-chaussée | no | 0 | 0 | 0 | 0 | Rez-de-chaussée (Rez-de-chaussée 1047) | 49.8355 | 55600 | 33100 | 18700 | 0
Fenêtre 23856 | Rez-de-chaussée | 317 | 121.149 | 23856 | 010 | 03 | Rez-de-chaussée | no | 0 | 0 | 0 | 0 | Rez-de-chaussée (Rez-de-chaussée 1047) | 49.8355 | 38400 | 19200 | 17000 | 0
Fenêtre 23877 | Rez-de-chaussée | 252 | 88.3246 | 23877 | 017 | 03 | Rez-de-chaussée | no | 0 | 0 | 0 | 0 | Rez-de-chaussée (Rez-de-chaussée 1047) | 50 | 22300 | 8600 | 12800 | 0
Fenêtre 23871 | Rez-de-chaussée | 316 | 116.31 | 23871 | 015 | 03 | Rez-de-chaussée | no | 0 | 0 | -2 | 0 | Rez-de-chaussée (Rez-de-chaussée 1047) | 48.9072 | 36800 | 18000 | 16700 | 0
Fenêtre 23874 | Rez-de-chaussée | 309 | 128.388 | 23874 | 016 | 03 | Rez-de-chaussée | no | 0 | 0 | 9 | 1 | Rez-de-chaussée (Rez-de-chaussée 1047) | 59.0331 | 39700 | 20400 | 16900 | 0
Fenêtre 23813 | Rez-de-chaussée | 255 | 126.72 | 23813 | 003 | 03 | Rez-de-chaussée | yes | 8 | 5 | -16 | 1 | Rez-de-chaussée (Rez-de-chaussée 1047) | 55.0123 | 32300 | 16100 | 14500 | 16800 | IFC_Pset_Géométrie_Ébrasement - Données: [a : 80,00; b: 0,00; c: 50,00; d: 0,00] mm
Fenêtre 103166 | Niveau 1 | 216 | 95.113 | 103166 | 033 | 04 | Niveau 1 | no | 0 | 0 | 0 | 1 | Niveau 1 (Niveau 1 2343) | 54.9 | 20500 | 8300 | 11500 | 0
Fenêtre 103158 | Niveau 1 | 235 | 109.572 | 103158 | 031 | 04 | Niveau 1 | no | 0 | 0 | 0 | 0 | Niveau 1 (Niveau 1 2343) | 54.9 | 25700 | 11600 | 12900 | 0
Fenêtre 103162 | Niveau 1 | 235 | 102.866 | 103162 | 032 | 04 | Niveau 1 | no | 0 | 0 | 0 | 0 | Niveau 1 (Niveau 1 2343) | 54.6 | 24200 | 10500 | 12600 | 0

# IfcWindow: FN[R] 2VB[2V] MM (2)
In: Niveau 1
Type - ParameterTakesPrecedence: no; Sizeable: no; Material: Transparent, Blanc trafic, Aluminium satiné
Type - IfcWindowLiningProperties - LiningDepth: 8 cm; LiningThickness: 5 cm
Type - IfcWindowPanelProperties - OperationType: FIXEDCASEMENT; FrameDepth: 0 cm; FrameThickness: 0 cm
Description: Fenêtre
__RECOGNIZE__ - TPLG: 101; TPLG_OD: 9004; GENERATE: 1
CTLG_EXTERNAL_LINK - 0, DocType: 3; 0, Tag: 100; 0, Crc: 1030203749; 1, DocType: 2; 1, Tag: 0; 1, Crc: -746779066; 2, DocType: 2; 2, Tag: 102; 2, Crc: -1731763687; 3, DocType: 2; 3, Tag: 104; 3, Crc: -623492449; 4, DocType: 2; 4, Tag: 105; 4, Crc: -1731763687; 5, DocType: 2; 5, Tag: 107; 5, Crc: -212966465
IFC_PSET_PolygonOffset - polygonOffsetFactor: 2; polygonOffsetUnits: 2
IFC_Pset_Caractéristiques - Numéro niveau: 04; Titre niveau: Niveau 1; Modèle 1re menuiserie: FN[R] 2VB[2V] MM
IFC_Pset_Géométrie_Allège - Hauteur: 0 cm; Stratigraphie: ...; Épaisseur: 0 cm
IFC_Pset_Géométrie_Ébrasement - Présent: no; Côté supérieur: no; Côté INFÉRIEUR: no; Épaisseur extérieure: 0 cm; Épaisseur latérale gauche: 0 cm; Épaisseur latérale droite: 0 cm; Épiasseur latérale supérieure: 0 cm; Épaisseur diagonale gauche: 0 cm; Épaisseur diagonale droite: 0 cm; Épaisseur diagonale inférieure: 0 cm; Épaisseur diagonale supérieure: 0 cm; Épaisseur intérieur: 0 cm
IFC_Pset_Géométrie_Seuil - Type: Aucun; Épaisseur: 0 cm; Épaisseur interne: 0 cm; Décalage séparation: 0 cm; Appui extérieur: 0 cm; Appui intérieur: 0 cm; Côté latéral externe: 0 cm; Côté latéral interne: 0 cm
IFC_Pset_Géométrie_Chambranle - Position: Aucun; Épaisseur Chambranle intérieur: 0 cm; Longueur Chambranle intérieur: 0 cm; Superposition Chambranle intérieur: 0 cm; Épaisseur Intrados: 0 cm; Épaisseur Chambranle extérieur: 0 cm; Largeur Chambranle extérieur: 0 cm; Superposition Chambranle extérieur: 0 cm; Épaisseur Intrados extérieur: 0 cm
IFC_Pset_Géométrie_CORNICHE depuis profil - Position: Aucune; sets with these values: 2
IFC_Pset_Géométrie_CORNICHE Extérieure à partir d'un profil - Décalage: 0; Angle: 0 deg; Symétrie: no; Fermer: no; sets with these values: 2
IFC_Pset_Géométrie_BASE Extérieure à partir d'un profil - Angle: 0 deg; Symétrie: no; Côté: 0 cm; sets with these values: 2
IFC_Pset_Géométrie_1° MENUISERIE - Position: Extérieur; Décalage: 0 cm
IFC_Pset_Géométrie_2° MENUISERIE - Décalage: 0 cm
IFC_Pset_Géométrie - Côté extérieur: 1; Invertir (dte/gche): no; Invertir (intérieur/extérieur): no; Hauteur 2: 0 cm; Rayon Arc: 0 cm; Rayon Cercle: 0 cm; Demi-axe horizontal: 0 cm; Demi-axe vertical: 0 cm
IFC_Pset_Géométrie_GRILLE - décalage: 0 cm; Offset latéral: 0 cm; Décalage supérieur: 0 cm; Décalage inférieur: 0 cm; Nombre accrochages latéraux: 0; Nombre d'accrochages supérieurs: 0; Nombre accrochages inférieurs: 0
IFC_Pset_Système de Référence Altimétrique_INFÉRIEUR - NIVEAU: Niveau 1 (Niveau 1 2343); delta: 0.0128504 cm; sous Niveau: <aucun>
IFC_Pset_Données Métré - Surface 1re Menuiserie: 25300 cm2; Surface Vitre 1re Menuiserie: 10500 cm2; Surface du Cadre de la 1re Menuiserie: 13700 cm2; Surface 2e Menuiserie: 0 cm2; Surface Vitre 2e Menuiserie: 0 cm2; Surface du Cadre de la 2ème Menuiserie: 0 cm2; Surface de l'Ouverture: 25300 cm2; Surface de l'Ébrasement: 0 cm2; Surface du Seuil: 0 cm2; Surface du Seuil intérieur: 0 cm2; Volume du seuil: 0 cm3; Volume du seuil intérieur: 0 cm3; Surface de la Grille: 0 cm2; Volume de la Grille: 0 cm3
IFC_Pset_Matériaux_1° MENUISERIE - Cadre externe: Blanc trafic; Verre: Transparent; Panneau extérieur: Blanc trafic; Poignée: Aluminium satiné
Pset_WindowCommon - Reference: FN[R] 2VB[2V] MM (..\Menuiserie simple\Fenêtre et Balcon\) <aucun>
Name | OverallHeight (cm) = Hauteur (cm) | OverallWidth (cm) = Largeur (cm) | __RECOGNIZE__, ID = IFC_Pset_Caractéristiques, ID | Numérotation
Fenêtre 121286 | 266.5 | 95.015 | 121286 | 043
Fenêtre 121285 | 267 | 94.6132 | 121285 | 042

# IfcWindow: FN[R] 2VB[2V] MM (5)
In: Niveau 1
Type - ParameterTakesPrecedence: no; Sizeable: no; Material: Transparent, Bleu france, Aluminium satiné
Type - IfcWindowLiningProperties - LiningDepth: 8 cm; LiningThickness: 5 cm
Type - IfcWindowPanelProperties - OperationType: FIXEDCASEMENT; FrameDepth: 0 cm; FrameThickness: 0 cm
Description: Fenêtre
__RECOGNIZE__ - TPLG: 101; TPLG_OD: 9004; GENERATE: 1
CTLG_EXTERNAL_LINK - 0, DocType: 3; 0, Tag: 100; 0, Crc: 1030203749; 1, DocType: 2; 1, Tag: 0; 1, Crc: -746779066; 2, DocType: 2; 2, Tag: 102; 2, Crc: 1181025438; 3, DocType: 2; 3, Tag: 104; 3, Crc: -623492449; 4, DocType: 2; 4, Tag: 105; 4, Crc: 1181025438; 5, DocType: 2; 5, Tag: 107; 5, Crc: -212966465
IFC_PSET_PolygonOffset - polygonOffsetFactor: 2; polygonOffsetUnits: 2
IFC_Pset_Caractéristiques - Numéro niveau: 04; Titre niveau: Niveau 1; Modèle 1re menuiserie: FN[R] 2VB[2V] MM
IFC_Pset_Géométrie_Allège - Hauteur: 0 cm; Stratigraphie: ...; Épaisseur: 0 cm
IFC_Pset_Géométrie_Ébrasement - Côté supérieur: no; Côté INFÉRIEUR: no; Épaisseur intérieur: 0 cm
IFC_Pset_Géométrie_Seuil - Type: Aucun; Épaisseur: 0 cm; Épaisseur interne: 0 cm; Décalage séparation: 0 cm; Appui extérieur: 0 cm; Appui intérieur: 0 cm; Côté latéral externe: 0 cm; Côté latéral interne: 0 cm
IFC_Pset_Géométrie_Chambranle - Position: Aucun; Épaisseur Chambranle intérieur: 0 cm; Longueur Chambranle intérieur: 0 cm; Superposition Chambranle intérieur: 0 cm; Épaisseur Intrados: 0 cm; Épaisseur Chambranle extérieur: 0 cm; Largeur Chambranle extérieur: 0 cm; Superposition Chambranle extérieur: 0 cm; Épaisseur Intrados extérieur: 0 cm
IFC_Pset_Géométrie_CORNICHE depuis profil - Position: Aucune; sets with these values: 2
IFC_Pset_Géométrie_CORNICHE Extérieure à partir d'un profil - Décalage: 0; Angle: 0 deg; Symétrie: no; Fermer: no; sets with these values: 2
IFC_Pset_Géométrie_BASE Extérieure à partir d'un profil - Angle: 0 deg; Symétrie: no; Côté: 0 cm; sets with these values: 2
IFC_Pset_Géométrie_1° MENUISERIE - Position: Extérieur; Décalage: 0 cm
IFC_Pset_Géométrie_2° MENUISERIE - Décalage: 0 cm
IFC_Pset_Géométrie - Invertir (dte/gche): no; Invertir (intérieur/extérieur): no; Hauteur 2: 0 cm; Rayon Arc: 0 cm; Rayon Cercle: 0 cm; Demi-axe horizontal: 0 cm; Demi-axe vertical: 0 cm
IFC_Pset_Géométrie_GRILLE - décalage: 0 cm; Offset latéral: 0 cm; Décalage supérieur: 0 cm; Décalage inférieur: 0 cm; Nombre accrochages latéraux: 0; Nombre d'accrochages supérieurs: 0; Nombre accrochages inférieurs: 0
IFC_Pset_Système de Référence Altimétrique_INFÉRIEUR - NIVEAU: Niveau 1 (Niveau 1 2343); sous Niveau: <aucun>
IFC_Pset_Données Métré - Surface 2e Menuiserie: 0 cm2; Surface Vitre 2e Menuiserie: 0 cm2; Surface du Cadre de la 2ème Menuiserie: 0 cm2; Surface du Seuil: 0 cm2; Surface du Seuil intérieur: 0 cm2; Volume du seuil: 0 cm3; Volume du seuil intérieur: 0 cm3; Surface de la Grille: 0 cm2; Volume de la Grille: 0 cm3
IFC_Pset_Matériaux_1° MENUISERIE - Cadre externe: Bleu france; Verre: Transparent; Panneau extérieur: Bleu france; Poignée: Aluminium satiné
Pset_WindowCommon - Reference: FN[R] 2VB[2V] MM (..\Menuiserie simple\Fenêtre et Balcon\) <aucun>
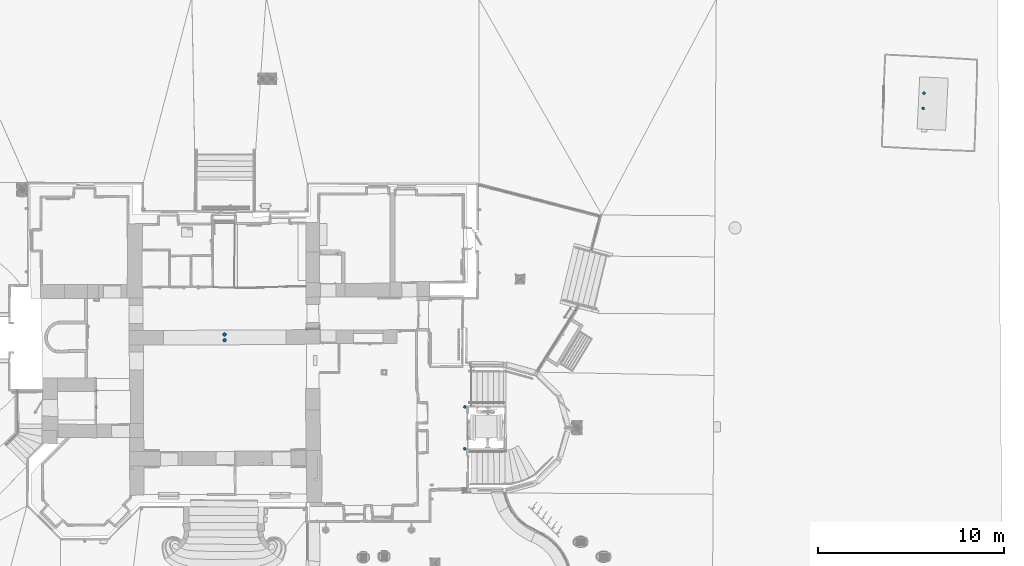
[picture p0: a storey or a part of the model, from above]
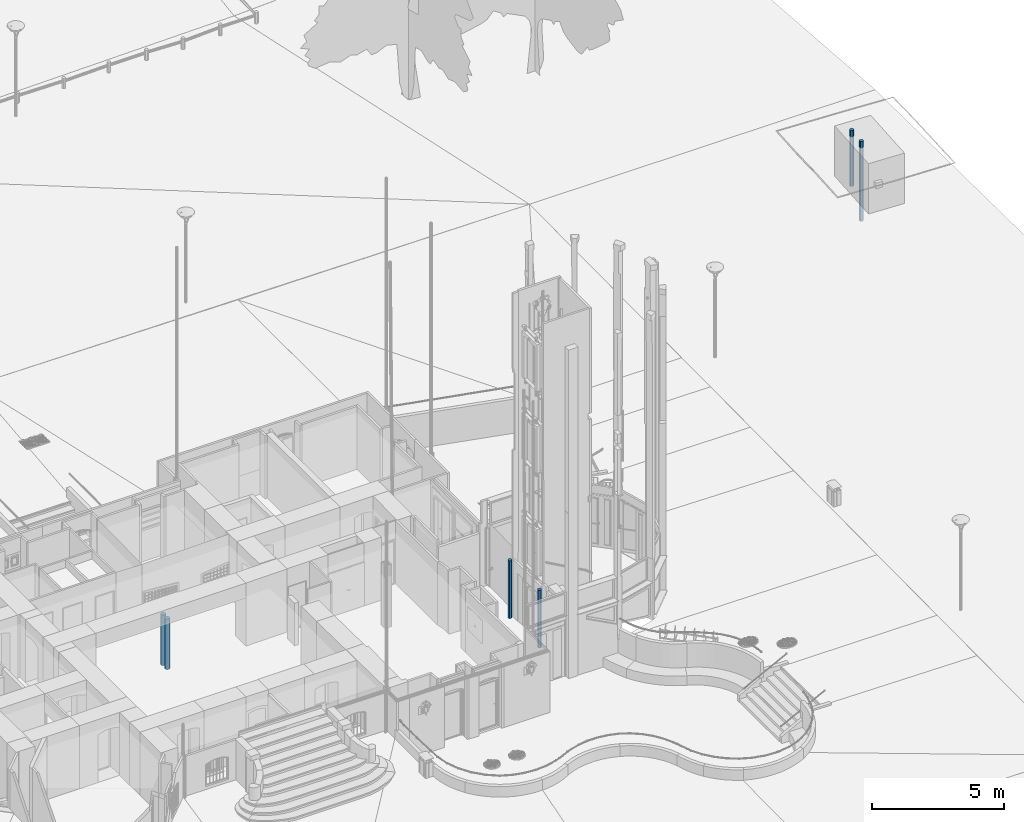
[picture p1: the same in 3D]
Properties of the parts of a building model (IFC2X3), part 36 of 37

# IfcWindow: FN[R] 2VB[2V] MM (5)
Name | OverallHeight (cm) = Hauteur (cm) | OverallWidth (cm) = Largeur (cm) | __RECOGNIZE__, ID = IFC_Pset_Caractéristiques, ID | Numérotation | Présent | Épaisseur extérieure (cm) | Épaisseur latérale gauche (cm) = Épaisseur latérale droite (cm) = Épiasseur latérale supérieure (cm) | Épaisseur diagonale gauche (cm) = Épaisseur diagonale inférieure (cm) = Épaisseur diagonale supérieure (cm) | Épaisseur diagonale droite (cm) | Côté extérieur | delta (cm) | Surface 1re Menuiserie (cm2) = Surface de l'Ouverture (cm2) | Surface Vitre 1re Menuiserie (cm2) | Surface du Cadre de la 1re Menuiserie (cm2) | Surface de l'Ébrasement (cm2) | Données
Fenêtre 103652 | 228 | 93.3169 | 103652 | 037 | no | 0 | 0 | 0 | 0 | 0 | 64.6 | 21300 | 8500 | 11900 | 0
Fenêtre 128673 | 268.2 | 104.964 | 128673 | 047 | yes | 6 | 2 | 2.5 | 3 | 1 | 1 | 28200 | 12600 | 14200 | 22600 | [a : 60,00; b: 20,00; c: 25,00; d: 0,00] mm
Fenêtre 128672 | 268.2 | 104.742 | 128672 | 046 | yes | 6 | 2 | 3 | 3 | 1 | 1 | 28100 | 12600 | 14200 | 22600 | [a : 60,00; b: 20,00; c: 30,00; d: 0,00] mm
Fenêtre 128668 | 268.2 | 104.638 | 128668 | 045 | yes | 6 | 2 | 2.5 | 3 | 1 | 1 | 28100 | 12600 | 14200 | 22600 | [a : 60,00; b: 20,00; c: 25,00; d: 0,00] mm
Fenêtre 128674 | 268.2 | 104.505 | 128674 | 048 | yes | 6 | 2 | 2.5 | 3 | 0 | 1 | 28000 | 12500 | 14200 | 22600 | [a : 60,00; b: 20,00; c: 25,00; d: 0,00] mm

# IfcWindow: FN[R] 2VB[2V] MM, Fenêtre 103199
In: Niveau 1
Type - ParameterTakesPrecedence: no; Sizeable: no; Material: Transparent, Bleu france, Noyer 01, Aluminium satiné
Type - IfcWindowLiningProperties - LiningDepth: 8 cm; LiningThickness: 5 cm
Type - IfcWindowPanelProperties - OperationType: FIXEDCASEMENT; FrameDepth: 0 cm; FrameThickness: 0 cm
Description: Fenêtre; OverallHeight: 234.405 cm; OverallWidth: 93.6147 cm
__RECOGNIZE__ - ID: 103199; TPLG: 101; TPLG_OD: 9004; GENERATE: 1
CTLG_EXTERNAL_LINK - 0, DocType: 3; 0, Tag: 100; 0, Crc: 1030203749; 1, DocType: 2; 1, Tag: 0; 1, Crc: -746779066; 2, DocType: 2; 2, Tag: 102; 2, Crc: 1181025438; 3, DocType: 2; 3, Tag: 104; 3, Crc: -623492449; 4, DocType: 2; 4, Tag: 105; 4, Crc: -990824515; 5, DocType: 2; 5, Tag: 107; 5, Crc: -212966465
IFC_PSET_PolygonOffset - polygonOffsetFactor: 2; polygonOffsetUnits: 2
IFC_Pset_Caractéristiques - ID: 103199; Numérotation: 034; Numéro niveau: 04; Titre niveau: Niveau 1; Modèle 1re menuiserie: FN[R] 2VB[2V] MM
IFC_Pset_Géométrie_Allège - Hauteur: 0 cm; Stratigraphie: ...; Épaisseur: 0 cm
IFC_Pset_Géométrie_Ébrasement - Présent: no; Côté supérieur: no; Côté INFÉRIEUR: no; Épaisseur extérieure: 0 cm; Épaisseur latérale gauche: 0 cm; Épaisseur latérale droite: 0 cm; Épiasseur latérale supérieure: 0 cm; Épaisseur diagonale gauche: 0 cm; Épaisseur diagonale droite: 0 cm; Épaisseur diagonale inférieure: 0 cm; Épaisseur diagonale supérieure: 0 cm; Épaisseur intérieur: 0 cm
IFC_Pset_Géométrie_Seuil - Type: Aucun; Épaisseur: 0 cm; Épaisseur interne: 0 cm; Décalage séparation: 0 cm; Appui extérieur: 0 cm; Appui intérieur: 0 cm; Côté latéral externe: 0 cm; Côté latéral interne: 0 cm
IFC_Pset_Géométrie_Chambranle - Position: Aucun; Épaisseur Chambranle intérieur: 0 cm; Longueur Chambranle intérieur: 0 cm; Superposition Chambranle intérieur: 0 cm; Épaisseur Intrados: 0 cm; Épaisseur Chambranle extérieur: 0 cm; Largeur Chambranle extérieur: 0 cm; Superposition Chambranle extérieur: 0 cm; Épaisseur Intrados extérieur: 0 cm
IFC_Pset_Géométrie_CORNICHE depuis profil - Position: Aucune; sets with these values: 2
IFC_Pset_Géométrie_CORNICHE Extérieure à partir d'un profil - Décalage: 0; Angle: 0 deg; Symétrie: no; Fermer: no; sets with these values: 2
IFC_Pset_Géométrie_BASE Extérieure à partir d'un profil - Angle: 0 deg; Symétrie: no; Côté: 0 cm; sets with these values: 2
IFC_Pset_Géométrie_1° MENUISERIE - Position: Extérieur; Décalage: 0 cm
IFC_Pset_Géométrie_2° MENUISERIE - Décalage: 0 cm
IFC_Pset_Géométrie - Côté extérieur: 0; Invertir (dte/gche): no; Invertir (intérieur/extérieur): no; Largeur: 93.6147 cm; Hauteur: 234.405 cm; Hauteur 2: 0 cm; Rayon Arc: 0 cm; Rayon Cercle: 0 cm; Demi-axe horizontal: 0 cm; Demi-axe vertical: 0 cm
IFC_Pset_Géométrie_GRILLE - décalage: 0 cm; Offset latéral: 0 cm; Décalage supérieur: 0 cm; Décalage inférieur: 0 cm; Nombre accrochages latéraux: 0; Nombre d'accrochages supérieurs: 0; Nombre accrochages inférieurs: 0
IFC_Pset_Système de Référence Altimétrique_INFÉRIEUR - NIVEAU: Niveau 1 (Niveau 1 2343); delta: 58.2 cm; sous Niveau: <aucun>
IFC_Pset_Données Métré - Surface 1re Menuiserie: 21900 cm2; Surface Vitre 1re Menuiserie: 8800 cm2; Surface du Cadre de la 1re Menuiserie: 12200 cm2; Surface 2e Menuiserie: 0 cm2; Surface Vitre 2e Menuiserie: 0 cm2; Surface du Cadre de la 2ème Menuiserie: 0 cm2; Surface de l'Ouverture: 21900 cm2; Surface de l'Ébrasement: 0 cm2; Surface du Seuil: 0 cm2; Surface du Seuil intérieur: 0 cm2; Volume du seuil: 0 cm3; Volume du seuil intérieur: 0 cm3; Surface de la Grille: 0 cm2; Volume de la Grille: 0 cm3
IFC_Pset_Matériaux_1° MENUISERIE - Cadre externe: Bleu france; Verre: Transparent; Panneau extérieur: Noyer 01; Poignée: Aluminium satiné
Pset_WindowCommon - Reference: FN[R] 2VB[2V] MM (..\Menuiserie simple\Fenêtre et Balcon\) <aucun>

# IfcWindow: FN[R] 2VB[2V] MM, Fenêtre 23810
In: Rez-de-chaussée
Type - ParameterTakesPrecedence: no; Sizeable: no; Material: Transparent, Gris vert, Blanc trafic (2), Aluminium satiné
Type - IfcWindowLiningProperties - LiningDepth: 8 cm; LiningThickness: 5 cm
Type - IfcWindowPanelProperties - OperationType: FIXEDCASEMENT; FrameDepth: 0 cm; FrameThickness: 0 cm
Description: Fenêtre; OverallHeight: 255 cm; OverallWidth: 125 cm
__RECOGNIZE__ - ID: 23810; TPLG: 101; TPLG_OD: 9004; GENERATE: 1
CTLG_EXTERNAL_LINK - 0, DocType: 3; 0, Tag: 100; 0, Crc: 1030203749; 1, DocType: 2; 1, Tag: 0; 1, Crc: -746779066; 2, DocType: 2; 2, Tag: 5; 2, Crc: 1596225049; 3, DocType: 2; 3, Tag: 102; 3, Crc: -1897652181; 4, DocType: 2; 4, Tag: 104; 4, Crc: -623492449; 5, DocType: 2; 5, Tag: 105; 5, Crc: -848491367; 6, DocType: 2; 6, Tag: 107; 6, Crc: -212966465
IFC_PSET_PolygonOffset - polygonOffsetFactor: 2; polygonOffsetUnits: 2
IFC_Pset_Caractéristiques - ID: 23810; Numérotation: 002; Numéro niveau: 03; Titre niveau: Rez-de-chaussée; Modèle 1re menuiserie: FN[R] 2VB[2V] MM
IFC_Pset_Géométrie_Allège - Hauteur: 0 cm; Stratigraphie: ...; Épaisseur: 0 cm
IFC_Pset_Géométrie_Ébrasement - Présent: yes; Côté supérieur: no; Côté INFÉRIEUR: no; Épaisseur extérieure: 8 cm; Épaisseur latérale gauche: 0 cm; Épaisseur latérale droite: 0 cm; Épiasseur latérale supérieure: 0 cm; Épaisseur diagonale gauche: 4 cm; Épaisseur diagonale droite: 5 cm; Épaisseur diagonale inférieure: 4 cm; Épaisseur diagonale supérieure: 4 cm; Épaisseur intérieur: 0 cm; Données: [a : 80,00; b: 0,00; c: 40,00; d: 0,00] mm
IFC_Pset_Géométrie_Seuil - Type: Aucun; Épaisseur: 0 cm; Épaisseur interne: 0 cm; Décalage séparation: 0 cm; Appui extérieur: 0 cm; Appui intérieur: 0 cm; Côté latéral externe: 0 cm; Côté latéral interne: 0 cm
IFC_Pset_Géométrie_Chambranle - Position: Aucun; Épaisseur Chambranle intérieur: 0 cm; Longueur Chambranle intérieur: 0 cm; Superposition Chambranle intérieur: 0 cm; Épaisseur Intrados: 0 cm; Épaisseur Chambranle extérieur: 0 cm; Largeur Chambranle extérieur: 0 cm; Superposition Chambranle extérieur: 0 cm; Épaisseur Intrados extérieur: 0 cm
IFC_Pset_Géométrie_CORNICHE depuis profil - Position: Aucune; sets with these values: 2
IFC_Pset_Géométrie_CORNICHE Extérieure à partir d'un profil - Décalage: 0; Angle: 0 deg; Symétrie: no; Fermer: no; sets with these values: 2
IFC_Pset_Géométrie_BASE Extérieure à partir d'un profil - Angle: 0 deg; Symétrie: no; Côté: 0 cm; sets with these values: 2
IFC_Pset_Géométrie_1° MENUISERIE - Position: Extérieur; Décalage: 5 cm
IFC_Pset_Géométrie_2° MENUISERIE - Décalage: 0 cm
IFC_Pset_Géométrie - Côté extérieur: 1; Invertir (dte/gche): no; Invertir (intérieur/extérieur): no; Largeur: 125 cm; Hauteur: 255 cm; Hauteur 2: 0 cm; Rayon Arc: 0 cm; Rayon Cercle: 0 cm; Demi-axe horizontal: 0 cm; Demi-axe vertical: 0 cm
IFC_Pset_Géométrie_GRILLE - décalage: 0 cm; Offset latéral: 0 cm; Décalage supérieur: 0 cm; Décalage inférieur: 0 cm; Nombre accrochages latéraux: 0; Nombre d'accrochages supérieurs: 0; Nombre accrochages inférieurs: 0
IFC_Pset_Système de Référence Altimétrique_INFÉRIEUR - NIVEAU: Rez-de-chaussée (Rez-de-chaussée 1047); delta: 55 cm; sous Niveau: <aucun>
IFC_Pset_Données Métré - Surface 1re Menuiserie: 31900 cm2; Surface Vitre 1re Menuiserie: 15800 cm2; Surface du Cadre de la 1re Menuiserie: 14400 cm2; Surface 2e Menuiserie: 0 cm2; Surface Vitre 2e Menuiserie: 0 cm2; Surface du Cadre de la 2ème Menuiserie: 0 cm2; Surface de l'Ouverture: 31900 cm2; Surface de l'Ébrasement: 21800 cm2; Surface du Seuil: 0 cm2; Surface du Seuil intérieur: 0 cm2; Volume du seuil: 0 cm3; Volume du seuil intérieur: 0 cm3; Surface de la Grille: 0 cm2; Volume de la Grille: 0 cm3
IFC_Pset_Matériaux - Chambranle Interne: Gris vert
IFC_Pset_Matériaux_1° MENUISERIE - Cadre externe: Blanc trafic; Verre: Transparent; Panneau extérieur: Blanc trafic; Poignée: Aluminium satiné
Pset_WindowCommon - Reference: FN[R] 2VB[2V] MM (..\Menuiserie simple\Fenêtre et Balcon\) <aucun>

# IfcWindow: FN[R] 2VB[2V] MM, Fenêtre 23816
In: Rez-de-chaussée
Type - ParameterTakesPrecedence: no; Sizeable: no; Material: Transparent, Noyer 01, Blanc trafic, Aluminium satiné
Type - IfcWindowLiningProperties - LiningDepth: 8 cm; LiningThickness: 5 cm
Type - IfcWindowPanelProperties - OperationType: FIXEDCASEMENT; FrameDepth: 0 cm; FrameThickness: 0 cm
Description: Fenêtre; OverallHeight: 180 cm; OverallWidth: 90 cm
__RECOGNIZE__ - ID: 23816; TPLG: 101; TPLG_OD: 9004; GENERATE: 1
CTLG_EXTERNAL_LINK - 0, DocType: 3; 0, Tag: 100; 0, Crc: 1030203749; 1, DocType: 2; 1, Tag: 0; 1, Crc: -746779066; 2, DocType: 2; 2, Tag: 102; 2, Crc: -848491367; 3, DocType: 2; 3, Tag: 104; 3, Crc: -623492449; 4, DocType: 2; 4, Tag: 105; 4, Crc: -990824515; 5, DocType: 2; 5, Tag: 107; 5, Crc: -212966465
IFC_PSET_PolygonOffset - polygonOffsetFactor: 2; polygonOffsetUnits: 2
IFC_Pset_Caractéristiques - ID: 23816; Numérotation: 004; Numéro niveau: 03; Titre niveau: Rez-de-chaussée; Modèle 1re menuiserie: FN[R] 2VB[2V] MM
IFC_Pset_Géométrie_Allège - Hauteur: 0 cm; Stratigraphie: ...; Épaisseur: 0 cm
IFC_Pset_Géométrie_Ébrasement - Présent: no; Côté supérieur: no; Côté INFÉRIEUR: no; Épaisseur extérieure: 0 cm; Épaisseur latérale gauche: 0 cm; Épaisseur latérale droite: 0 cm; Épiasseur latérale supérieure: 0 cm; Épaisseur diagonale gauche: 0 cm; Épaisseur diagonale droite: 0 cm; Épaisseur diagonale inférieure: 0 cm; Épaisseur diagonale supérieure: 0 cm; Épaisseur intérieur: 0 cm
IFC_Pset_Géométrie_Seuil - Type: Aucun; Épaisseur: 0 cm; Épaisseur interne: 0 cm; Décalage séparation: 0 cm; Appui extérieur: 0 cm; Appui intérieur: 0 cm; Côté latéral externe: 0 cm; Côté latéral interne: 0 cm
IFC_Pset_Géométrie_Chambranle - Position: Aucun; Épaisseur Chambranle intérieur: 0 cm; Longueur Chambranle intérieur: 0 cm; Superposition Chambranle intérieur: 0 cm; Épaisseur Intrados: 0 cm; Épaisseur Chambranle extérieur: 0 cm; Largeur Chambranle extérieur: 0 cm; Superposition Chambranle extérieur: 0 cm; Épaisseur Intrados extérieur: 0 cm
IFC_Pset_Géométrie_CORNICHE depuis profil - Position: Aucune; sets with these values: 2
IFC_Pset_Géométrie_CORNICHE Extérieure à partir d'un profil - Décalage: 0; Angle: 0 deg; Symétrie: no; Fermer: no; sets with these values: 2
IFC_Pset_Géométrie_BASE Extérieure à partir d'un profil - Angle: 0 deg; Symétrie: no; Côté: 0 cm; sets with these values: 2
IFC_Pset_Géométrie_1° MENUISERIE - Position: Extérieur; Décalage: 0 cm
IFC_Pset_Géométrie_2° MENUISERIE - Décalage: 0 cm
IFC_Pset_Géométrie - Côté extérieur: 0; Invertir (dte/gche): no; Invertir (intérieur/extérieur): no; Largeur: 90 cm; Hauteur: 180 cm; Hauteur 2: 0 cm; Rayon Arc: 0 cm; Rayon Cercle: 0 cm; Demi-axe horizontal: 0 cm; Demi-axe vertical: 0 cm
IFC_Pset_Géométrie_GRILLE - décalage: 0 cm; Offset latéral: 0 cm; Décalage supérieur: 0 cm; Décalage inférieur: 0 cm; Nombre accrochages latéraux: 0; Nombre d'accrochages supérieurs: 0; Nombre accrochages inférieurs: 0
IFC_Pset_Système de Référence Altimétrique_INFÉRIEUR - NIVEAU: Rez-de-chaussée (Rez-de-chaussée 1047); delta: 50 cm; sous Niveau: <aucun>
IFC_Pset_Données Métré - Surface 1re Menuiserie: 16200 cm2; Surface Vitre 1re Menuiserie: 6000 cm2; Surface du Cadre de la 1re Menuiserie: 9700 cm2; Surface 2e Menuiserie: 0 cm2; Surface Vitre 2e Menuiserie: 0 cm2; Surface du Cadre de la 2ème Menuiserie: 0 cm2; Surface de l'Ouverture: 16200 cm2; Surface de l'Ébrasement: 0 cm2; Surface du Seuil: 0 cm2; Surface du Seuil intérieur: 0 cm2; Volume du seuil: 0 cm3; Volume du seuil intérieur: 0 cm3; Surface de la Grille: 0 cm2; Volume de la Grille: 0 cm3
IFC_Pset_Matériaux_1° MENUISERIE - Cadre externe: Blanc trafic; Verre: Transparent; Panneau extérieur: Noyer 01; Poignée: Aluminium satiné
Pset_WindowCommon - Reference: FN[R] 2VB[2V] MM (..\Menuiserie simple\Fenêtre et Balcon\) <aucun>

# IfcWindow: FN[R] 2VB[2V] MM, Fenêtre 115412
In: Niveau 1
Type - ParameterTakesPrecedence: no; Sizeable: no; Material: Transparent, Vert clair_porte, Aluminium satiné
Type - IfcWindowLiningProperties - LiningDepth: 8 cm; LiningThickness: 5 cm
Type - IfcWindowPanelProperties - OperationType: FIXEDCASEMENT; FrameDepth: 0 cm; FrameThickness: 0 cm
Description: Fenêtre; OverallHeight: 237 cm; OverallWidth: 98.3512 cm
__RECOGNIZE__ - ID: 115412; TPLG: 101; TPLG_OD: 9004; GENERATE: 1
CTLG_EXTERNAL_LINK - 0, DocType: 3; 0, Tag: 100; 0, Crc: 1030203749; 1, DocType: 2; 1, Tag: 0; 1, Crc: -746779066; 2, DocType: 2; 2, Tag: 102; 2, Crc: -1022614176; 3, DocType: 2; 3, Tag: 104; 3, Crc: -623492449; 4, DocType: 2; 4, Tag: 105; 4, Crc: -1022614176; 5, DocType: 2; 5, Tag: 107; 5, Crc: -212966465
IFC_PSET_PolygonOffset - polygonOffsetFactor: 2; polygonOffsetUnits: 2
IFC_Pset_Caractéristiques - ID: 115412; Numérotation: 040; Numéro niveau: 04; Titre niveau: Niveau 1; Modèle 1re menuiserie: FN[R] 2VB[2V] MM
IFC_Pset_Géométrie_Allège - Hauteur: 0 cm; Stratigraphie: ...; Épaisseur: 0 cm
IFC_Pset_Géométrie_Ébrasement - Présent: no; Côté supérieur: no; Côté INFÉRIEUR: no; Épaisseur extérieure: 0 cm; Épaisseur latérale gauche: 0 cm; Épaisseur latérale droite: 0 cm; Épiasseur latérale supérieure: 0 cm; Épaisseur diagonale gauche: 0 cm; Épaisseur diagonale droite: 0 cm; Épaisseur diagonale inférieure: 0 cm; Épaisseur diagonale supérieure: 0 cm; Épaisseur intérieur: 0 cm
IFC_Pset_Géométrie_Seuil - Type: Aucun; Épaisseur: 0 cm; Épaisseur interne: 0 cm; Décalage séparation: 0 cm; Appui extérieur: 0 cm; Appui intérieur: 0 cm; Côté latéral externe: 0 cm; Côté latéral interne: 0 cm
IFC_Pset_Géométrie_Chambranle - Position: Aucun; Épaisseur Chambranle intérieur: 0 cm; Longueur Chambranle intérieur: 0 cm; Superposition Chambranle intérieur: 0 cm; Épaisseur Intrados: 0 cm; Épaisseur Chambranle extérieur: 0 cm; Largeur Chambranle extérieur: 0 cm; Superposition Chambranle extérieur: 0 cm; Épaisseur Intrados extérieur: 0 cm
IFC_Pset_Géométrie_CORNICHE depuis profil - Position: Aucune; sets with these values: 2
IFC_Pset_Géométrie_CORNICHE Extérieure à partir d'un profil - Décalage: 0; Angle: 0 deg; Symétrie: no; Fermer: no; sets with these values: 2
IFC_Pset_Géométrie_BASE Extérieure à partir d'un profil - Angle: 0 deg; Symétrie: no; Côté: 0 cm; sets with these values: 2
IFC_Pset_Géométrie_1° MENUISERIE - Position: Extérieur; Décalage: 0 cm
IFC_Pset_Géométrie_2° MENUISERIE - Décalage: 0 cm
IFC_Pset_Géométrie - Côté extérieur: 0; Invertir (dte/gche): no; Invertir (intérieur/extérieur): no; Largeur: 98.3512 cm; Hauteur: 237 cm; Hauteur 2: 0 cm; Rayon Arc: 0 cm; Rayon Cercle: 0 cm; Demi-axe horizontal: 0 cm; Demi-axe vertical: 0 cm
IFC_Pset_Géométrie_GRILLE - décalage: 0 cm; Offset latéral: 0 cm; Décalage supérieur: 0 cm; Décalage inférieur: 0 cm; Nombre accrochages latéraux: 0; Nombre d'accrochages supérieurs: 0; Nombre accrochages inférieurs: 0
IFC_Pset_Système de Référence Altimétrique_INFÉRIEUR - NIVEAU: Niveau 1 (Niveau 1 2343); delta: 57 cm; sous Niveau: <aucun>
IFC_Pset_Données Métré - Surface 1re Menuiserie: 23300 cm2; Surface Vitre 1re Menuiserie: 9800 cm2; Surface du Cadre de la 1re Menuiserie: 12500 cm2; Surface 2e Menuiserie: 0 cm2; Surface Vitre 2e Menuiserie: 0 cm2; Surface du Cadre de la 2ème Menuiserie: 0 cm2; Surface de l'Ouverture: 23300 cm2; Surface de l'Ébrasement: 0 cm2; Surface du Seuil: 0 cm2; Surface du Seuil intérieur: 0 cm2; Volume du seuil: 0 cm3; Volume du seuil intérieur: 0 cm3; Surface de la Grille: 0 cm2; Volume de la Grille: 0 cm3
IFC_Pset_Matériaux_1° MENUISERIE - Cadre externe: Vert clair_porte; Verre: Transparent; Panneau extérieur: Vert clair_porte; Poignée: Aluminium satiné
Pset_WindowCommon - Reference: FN[R] 2VB[2V] MM (..\Menuiserie simple\Fenêtre et Balcon\) <aucun>

# IfcWindow: FN[R] 2VB[2V] MM, Fenêtre 115415
In: Niveau 1
Type - ParameterTakesPrecedence: no; Sizeable: no; Material: Transparent, Vert clair_porte, Noyer 01, Aluminium satiné
Type - IfcWindowLiningProperties - LiningDepth: 8 cm; LiningThickness: 5 cm
Type - IfcWindowPanelProperties - OperationType: FIXEDCASEMENT; FrameDepth: 0 cm; FrameThickness: 0 cm
Description: Fenêtre; OverallHeight: 212.703 cm; OverallWidth: 96.0682 cm
__RECOGNIZE__ - ID: 115415; TPLG: 101; TPLG_OD: 9004; GENERATE: 1
CTLG_EXTERNAL_LINK - 0, DocType: 3; 0, Tag: 100; 0, Crc: 1030203749; 1, DocType: 2; 1, Tag: 0; 1, Crc: -746779066; 2, DocType: 2; 2, Tag: 102; 2, Crc: -1022614176; 3, DocType: 2; 3, Tag: 104; 3, Crc: -623492449; 4, DocType: 2; 4, Tag: 105; 4, Crc: -990824515; 5, DocType: 2; 5, Tag: 107; 5, Crc: -212966465
IFC_PSET_PolygonOffset - polygonOffsetFactor: 2; polygonOffsetUnits: 2
IFC_Pset_Caractéristiques - ID: 115415; Numérotation: 041; Numéro niveau: 04; Titre niveau: Niveau 1; Modèle 1re menuiserie: FN[R] 2VB[2V] MM
IFC_Pset_Géométrie_Allège - Hauteur: 0 cm; Stratigraphie: ...; Épaisseur: 0 cm
IFC_Pset_Géométrie_Ébrasement - Présent: no; Côté supérieur: no; Côté INFÉRIEUR: no; Épaisseur extérieure: 0 cm; Épaisseur latérale gauche: 0 cm; Épaisseur latérale droite: 0 cm; Épiasseur latérale supérieure: 0 cm; Épaisseur diagonale gauche: 0 cm; Épaisseur diagonale droite: 0 cm; Épaisseur diagonale inférieure: 0 cm; Épaisseur diagonale supérieure: 0 cm; Épaisseur intérieur: 0 cm
IFC_Pset_Géométrie_Seuil - Type: Aucun; Épaisseur: 0 cm; Épaisseur interne: 0 cm; Décalage séparation: 0 cm; Appui extérieur: 0 cm; Appui intérieur: 0 cm; Côté latéral externe: 0 cm; Côté latéral interne: 0 cm
IFC_Pset_Géométrie_Chambranle - Position: Aucun; Épaisseur Chambranle intérieur: 0 cm; Longueur Chambranle intérieur: 0 cm; Superposition Chambranle intérieur: 0 cm; Épaisseur Intrados: 0 cm; Épaisseur Chambranle extérieur: 0 cm; Largeur Chambranle extérieur: 0 cm; Superposition Chambranle extérieur: 0 cm; Épaisseur Intrados extérieur: 0 cm
IFC_Pset_Géométrie_CORNICHE depuis profil - Position: Aucune; sets with these values: 2
IFC_Pset_Géométrie_CORNICHE Extérieure à partir d'un profil - Décalage: 0; Angle: 0 deg; Symétrie: no; Fermer: no; sets with these values: 2
IFC_Pset_Géométrie_BASE Extérieure à partir d'un profil - Angle: 0 deg; Symétrie: no; Côté: 0 cm; sets with these values: 2
IFC_Pset_Géométrie_1° MENUISERIE - Position: Extérieur; Décalage: 0 cm
IFC_Pset_Géométrie_2° MENUISERIE - Décalage: 0 cm
IFC_Pset_Géométrie - Côté extérieur: 0; Invertir (dte/gche): no; Invertir (intérieur/extérieur): no; Largeur: 96.0682 cm; Hauteur: 212.703 cm; Hauteur 2: 0 cm; Rayon Arc: 0 cm; Rayon Cercle: 0 cm; Demi-axe horizontal: 0 cm; Demi-axe vertical: 0 cm
IFC_Pset_Géométrie_GRILLE - décalage: 0 cm; Offset latéral: 0 cm; Décalage supérieur: 0 cm; Décalage inférieur: 0 cm; Nombre accrochages latéraux: 0; Nombre d'accrochages supérieurs: 0; Nombre accrochages inférieurs: 0
IFC_Pset_Système de Référence Altimétrique_INFÉRIEUR - NIVEAU: Niveau 1 (Niveau 1 2343); delta: 56.5 cm; sous Niveau: <aucun>
IFC_Pset_Données Métré - Surface 1re Menuiserie: 20400 cm2; Surface Vitre 1re Menuiserie: 8200 cm2; Surface du Cadre de la 1re Menuiserie: 11400 cm2; Surface 2e Menuiserie: 0 cm2; Surface Vitre 2e Menuiserie: 0 cm2; Surface du Cadre de la 2ème Menuiserie: 0 cm2; Surface de l'Ouverture: 20400 cm2; Surface de l'Ébrasement: 0 cm2; Surface du Seuil: 0 cm2; Surface du Seuil intérieur: 0 cm2; Volume du seuil: 0 cm3; Volume du seuil intérieur: 0 cm3; Surface de la Grille: 0 cm2; Volume de la Grille: 0 cm3
IFC_Pset_Matériaux_1° MENUISERIE - Cadre externe: Vert clair_porte; Verre: Transparent; Panneau extérieur: Noyer 01; Poignée: Aluminium satiné
Pset_WindowCommon - Reference: FN[R] 2VB[2V] MM (..\Menuiserie simple\Fenêtre et Balcon\) <aucun>

# IfcWindow: FT[R] 1AB[1V] (7)
In: Couverture
Type - OperationType: SINGLE_PANEL; ParameterTakesPrecedence: yes; Sizeable: no; Material: Transparent, Blanc
Type - IfcWindowLiningProperties - LiningDepth: 8 cm; LiningThickness: 5 cm
Type - IfcWindowPanelProperties - OperationType: FIXEDCASEMENT; PanelPosition: MIDDLE; FrameDepth: 7 cm; FrameThickness: 5 cm
Description: Fenêtre
__RECOGNIZE__ - TPLG: 101; TPLG_OD: 9004; GENERATE: 1
CTLG_EXTERNAL_LINK - 0, DocType: 3; 0, Tag: 100; 0, Crc: -2074747957; 1, DocType: 2; 1, Tag: 0; 1, Crc: -746779066; 2, DocType: 2; 2, Tag: 102; 2, Crc: -490719661; 3, DocType: 2; 3, Tag: 104; 3, Crc: -623492449
IFC_PSET_PolygonOffset - polygonOffsetFactor: 2; polygonOffsetUnits: 2
IFC_Pset_Caractéristiques - Numéro niveau: 07; Titre niveau: Couverture; Modèle 1re menuiserie: FT[R] 1AB[1V]
IFC_Pset_Géométrie_Allège - Hauteur: 0 cm; Stratigraphie: ...; Épaisseur: 0 cm
IFC_Pset_Géométrie_Ébrasement - Présent: no; Côté supérieur: no; Côté INFÉRIEUR: no; Épaisseur extérieure: 0 cm; Épaisseur latérale gauche: 0 cm; Épaisseur latérale droite: 0 cm; Épiasseur latérale supérieure: 0 cm; Épaisseur diagonale gauche: 0 cm; Épaisseur diagonale droite: 0 cm; Épaisseur diagonale inférieure: 0 cm; Épaisseur diagonale supérieure: 0 cm; Épaisseur intérieur: 0 cm
IFC_Pset_Géométrie_Seuil - Type: Aucun; Épaisseur: 0 cm; Épaisseur interne: 0 cm; Décalage séparation: 0 cm; Appui extérieur: 0 cm; Appui intérieur: 0 cm; Côté latéral externe: 0 cm; Côté latéral interne: 0 cm
IFC_Pset_Géométrie_Chambranle - Position: Aucun; Épaisseur Chambranle intérieur: 0 cm; Longueur Chambranle intérieur: 0 cm; Superposition Chambranle intérieur: 0 cm; Épaisseur Intrados: 0 cm; Épaisseur Chambranle extérieur: 0 cm; Largeur Chambranle extérieur: 0 cm; Superposition Chambranle extérieur: 0 cm; Épaisseur Intrados extérieur: 0 cm
IFC_Pset_Géométrie_CORNICHE depuis profil - Position: Aucune; sets with these values: 2
IFC_Pset_Géométrie_CORNICHE Extérieure à partir d'un profil - Décalage: 0; Angle: 0 deg; Symétrie: no; Fermer: no; sets with these values: 2
IFC_Pset_Géométrie_BASE Extérieure à partir d'un profil - Angle: 0 deg; Symétrie: no; Côté: 0 cm; sets with these values: 2
IFC_Pset_Géométrie_1° MENUISERIE - Décalage: 0 cm
IFC_Pset_Géométrie_2° MENUISERIE - Décalage: 0 cm
IFC_Pset_Géométrie - Côté extérieur: 0; Invertir (dte/gche): no; Invertir (intérieur/extérieur): no; Hauteur 2: 0 cm; Rayon Arc: 0 cm; Rayon Cercle: 0 cm; Demi-axe horizontal: 0 cm; Demi-axe vertical: 0 cm
IFC_Pset_Géométrie_GRILLE - décalage: 0 cm; Offset latéral: 0 cm; Décalage supérieur: 0 cm; Décalage inférieur: 0 cm; Nombre accrochages latéraux: 0; Nombre d'accrochages supérieurs: 0; Nombre accrochages inférieurs: 0
IFC_Pset_Système de Référence Altimétrique_INFÉRIEUR - NIVEAU: Couverture (Couverture 2134); delta: 0 cm; sous Niveau: <aucun>
IFC_Pset_Données Métré - Surface 2e Menuiserie: 0 cm2; Surface Vitre 2e Menuiserie: 0 cm2; Surface du Cadre de la 2ème Menuiserie: 0 cm2; Surface de l'Ébrasement: 0 cm2; Surface du Seuil: 0 cm2; Surface du Seuil intérieur: 0 cm2; Volume du seuil: 0 cm3; Volume du seuil intérieur: 0 cm3; Surface de la Grille: 0 cm2; Volume de la Grille: 0 cm3
IFC_Pset_Matériaux_1° MENUISERIE - Cadre externe: Blanc; Verre: Transparent
Pset_WindowCommon - Reference: FT[R] 1AB[1V] (..\Menuiserie classique\Fenêtres pour toits\) <aucun>
Name | OverallHeight (cm) = Hauteur (cm) | OverallWidth (cm) = Largeur (cm) | __RECOGNIZE__, ID = IFC_Pset_Caractéristiques, ID | Numérotation | Position | Surface 1re Menuiserie (cm2) = Surface de l'Ouverture (cm2) | Surface Vitre 1re Menuiserie (cm2) | Surface du Cadre de la 1re Menuiserie (cm2)
Fenêtre 905746 | 62 | 66 | 905746 | 118 | Extérieur | 4100 | 1600 | 2500
Fenêtre 836189 | 98 | 118 | 836189 | 117 | Extérieur | 11600 | 7000 | 4600
Fenêtre 926055 | 97 | 114 | 926055 | 122 | Extérieur | 11100 | 6600 | 4500
Fenêtre 924501 | 78 | 114 | 924501 | 121 | Extérieur | 8900 | 4900 | 4000
Fenêtre 915628 | 78 | 114 | 915628 | 120 | Extérieur | 8900 | 4900 | 4000
Fenêtre 914843 | 78 | 114 | 914843 | 119 | Extérieur | 8900 | 4900 | 4000
Fenêtre 1979216 | 118 | 114 | 1979216 | 132 | Centre | 13500 | 8500 | 5000

# IfcWindow: F[R] VV (4)
Type - OperationType: SINGLE_PANEL; ParameterTakesPrecedence: yes; Sizeable: no; Material: Transparent, Blanc trafic
Type - IfcWindowLiningProperties - LiningDepth: 7 cm; LiningThickness: 6.5 cm
Type - IfcWindowPanelProperties - OperationType: FIXEDCASEMENT; PanelPosition: MIDDLE; FrameDepth: 7 cm; FrameThickness: 6.5 cm
Description: Fenêtre
__RECOGNIZE__ - TPLG: 101; TPLG_OD: 9004; GENERATE: 1
CTLG_EXTERNAL_LINK - 0, DocType: 3; 0, Tag: 100; 0, Crc: 374824113; 1, DocType: 2; 1, Tag: 0; 1, Crc: -746779066; 2, DocType: 2; 2, Tag: 102; 3, DocType: 2; 3, Tag: 104; 3, Crc: -623492449
IFC_PSET_PolygonOffset - polygonOffsetFactor: 2; polygonOffsetUnits: 2
IFC_Pset_Caractéristiques - Modèle 1re menuiserie: F[R] VV
IFC_Pset_Géométrie_Allège - Hauteur: 0 cm; Stratigraphie: ...; Épaisseur: 0 cm
IFC_Pset_Géométrie_Ébrasement - Présent: no; Côté supérieur: no; Côté INFÉRIEUR: no; Épaisseur extérieure: 0 cm; Épaisseur latérale gauche: 0 cm; Épaisseur latérale droite: 0 cm; Épiasseur latérale supérieure: 0 cm; Épaisseur diagonale gauche: 0 cm; Épaisseur diagonale droite: 0 cm; Épaisseur diagonale inférieure: 0 cm; Épaisseur diagonale supérieure: 0 cm; Épaisseur intérieur: 0 cm
IFC_Pset_Géométrie_Seuil - Type: Aucun; Épaisseur: 0 cm; Épaisseur interne: 0 cm; Décalage séparation: 0 cm; Appui extérieur: 0 cm; Appui intérieur: 0 cm; Côté latéral externe: 0 cm; Côté latéral interne: 0 cm
IFC_Pset_Géométrie_Chambranle - Position: Aucun; Épaisseur Chambranle intérieur: 0 cm; Longueur Chambranle intérieur: 0 cm; Superposition Chambranle intérieur: 0 cm; Épaisseur Intrados: 0 cm; Épaisseur Chambranle extérieur: 0 cm; Largeur Chambranle extérieur: 0 cm; Superposition Chambranle extérieur: 0 cm; Épaisseur Intrados extérieur: 0 cm
IFC_Pset_Géométrie_CORNICHE depuis profil - Position: Aucune; sets with these values: 2
IFC_Pset_Géométrie_CORNICHE Extérieure à partir d'un profil - Décalage: 0; Angle: 0 deg; Symétrie: no; Fermer: no; sets with these values: 2
IFC_Pset_Géométrie_BASE Extérieure à partir d'un profil - Angle: 0 deg; Symétrie: no; Côté: 0 cm; sets with these values: 2
IFC_Pset_Géométrie_2° MENUISERIE - Décalage: 0 cm
IFC_Pset_Géométrie - Invertir (dte/gche): no; Invertir (intérieur/extérieur): no; Hauteur 2: 0 cm; Rayon Arc: 0 cm; Rayon Cercle: 0 cm; Demi-axe horizontal: 0 cm; Demi-axe vertical: 0 cm
IFC_Pset_Géométrie_GRILLE - décalage: 0 cm; Offset latéral: 0 cm; Décalage supérieur: 0 cm; Décalage inférieur: 0 cm; Nombre accrochages latéraux: 0; Nombre d'accrochages supérieurs: 0; Nombre accrochages inférieurs: 0
IFC_Pset_Système de Référence Altimétrique_INFÉRIEUR - sous Niveau: <aucun>
IFC_Pset_Données Métré - Surface 2e Menuiserie: 0 cm2; Surface Vitre 2e Menuiserie: 0 cm2; Surface du Cadre de la 2ème Menuiserie: 0 cm2; Surface de l'Ébrasement: 0 cm2; Surface du Seuil: 0 cm2; Surface du Seuil intérieur: 0 cm2; Volume du seuil: 0 cm3; Volume du seuil intérieur: 0 cm3; Surface de la Grille: 0 cm2; Volume de la Grille: 0 cm3
IFC_Pset_Matériaux_1° MENUISERIE - Cadre externe: Blanc trafic; Verre: Transparent
Pset_WindowCommon - Reference: F[R] VV (..\IDEAL 5000 eko okna\) <aucun>
Name | In | OverallHeight (cm) = Hauteur (cm) | OverallWidth (cm) = Largeur (cm) | __RECOGNIZE__, ID = IFC_Pset_Caractéristiques, ID | 2, Crc | Numérotation | Numéro niveau | Titre niveau | Position | Décalage (cm) | Côté extérieur | NIVEAU | delta (cm) | Surface 1re Menuiserie (cm2) = Surface de l'Ouverture (cm2) | Surface Vitre 1re Menuiserie (cm2) | Surface du Cadre de la 1re Menuiserie (cm2)
Fenêtre 728288 | Niveau 1 | 355 | 144.325 | 728288 | -848491367 | 113 | 04 | Niveau 1 | Extérieur | 0 | 1 | Niveau 1 (Niveau 1 2343) | -5.00002 | 51200 | 44900 | 6300
Fenêtre 728354 | Niveau 2 | 220.938 | 164.223 | 728354 | -848491367 | 115 | 05 | Niveau 2 | Extérieur | 4.5 | 0 | Niveau 2 (Niveau 2 13545) | -4.74692 | 36300 | 31400 | 4800
Fenêtre 1705934 | Niveau 2 | 158 | 87.9552 | 1705934 | 1192038750 | 131 | 05 | Niveau 2 | Centre | 0 | 0 | Niveau 2 (Niveau 2 13545) | 64 | 13900 | 10900 | 3000
Fenêtre 1705931 | Niveau 2 | 158 | 89.5689 | 1705931 | 1192038750 | 130 | 05 | Niveau 2 | Centre | 0 | 0 | Niveau 2 (Niveau 2 13545) | 64 | 14200 | 11100 | 3000

# IfcWindow: F[R] VV (8)
Type - OperationType: SINGLE_PANEL; ParameterTakesPrecedence: yes; Sizeable: no; Material: Transparent, Blanc trafic (2)
Type - IfcWindowLiningProperties - LiningDepth: 7 cm; LiningThickness: 6.5 cm
Type - IfcWindowPanelProperties - OperationType: FIXEDCASEMENT; PanelPosition: MIDDLE; FrameDepth: 7 cm; FrameThickness: 6.5 cm
Description: Fenêtre
__RECOGNIZE__ - TPLG: 101; TPLG_OD: 9004; GENERATE: 1
CTLG_EXTERNAL_LINK - 0, DocType: 3; 0, Tag: 100; 0, Crc: 374824113; 1, DocType: 2; 1, Tag: 0; 1, Crc: -746779066; 2, DocType: 2; 2, Tag: 15; 2, Crc: -848491367; 3, DocType: 2; 3, Tag: 102; 3, Crc: -1731763687; 4, DocType: 2; 4, Tag: 104; 4, Crc: -623492449
IFC_PSET_PolygonOffset - polygonOffsetFactor: 2; polygonOffsetUnits: 2
IFC_Pset_Caractéristiques - Modèle 1re menuiserie: F[R] VV
IFC_Pset_Géométrie_Allège - Hauteur: 0 cm; Stratigraphie: ...; Épaisseur: 0 cm
IFC_Pset_Géométrie_Ébrasement - Côté supérieur: no; Côté INFÉRIEUR: no; Épaisseur intérieur: 0 cm
IFC_Pset_Géométrie_Seuil - Type: Unique; Épaisseur: 3 cm; Épaisseur interne: 3 cm; Décalage séparation: 0 cm; Appui extérieur: 0 cm; Côté latéral externe: 0 cm; Côté latéral interne: 5 cm
IFC_Pset_Géométrie_Chambranle - Position: Aucun; Épaisseur Chambranle intérieur: 0 cm; Longueur Chambranle intérieur: 0 cm; Superposition Chambranle intérieur: 0 cm; Épaisseur Intrados: 0 cm; Épaisseur Chambranle extérieur: 0 cm; Largeur Chambranle extérieur: 0 cm; Superposition Chambranle extérieur: 0 cm; Épaisseur Intrados extérieur: 0 cm
IFC_Pset_Géométrie_CORNICHE depuis profil - Position: Aucune; sets with these values: 2
IFC_Pset_Géométrie_CORNICHE Extérieure à partir d'un profil - Décalage: 0; Angle: 0 deg; Symétrie: no; Fermer: no; sets with these values: 2
IFC_Pset_Géométrie_BASE Extérieure à partir d'un profil - Angle: 0 deg; Symétrie: no; Côté: 0 cm; sets with these values: 2
IFC_Pset_Géométrie_1° MENUISERIE - Position: Centre
IFC_Pset_Géométrie_2° MENUISERIE - Décalage: 0 cm
IFC_Pset_Géométrie - Côté extérieur: 0; Invertir (dte/gche): no; Hauteur 2: 0 cm; Rayon Arc: 0 cm; Rayon Cercle: 0 cm; Demi-axe horizontal: 0 cm; Demi-axe vertical: 0 cm
IFC_Pset_Géométrie_GRILLE - décalage: 0 cm; Offset latéral: 0 cm; Décalage supérieur: 0 cm; Décalage inférieur: 0 cm; Nombre accrochages latéraux: 0; Nombre d'accrochages supérieurs: 0; Nombre accrochages inférieurs: 0
IFC_Pset_Système de Référence Altimétrique_INFÉRIEUR - sous Niveau: <aucun>
IFC_Pset_Données Métré - Surface 2e Menuiserie: 0 cm2; Surface Vitre 2e Menuiserie: 0 cm2; Surface du Cadre de la 2ème Menuiserie: 0 cm2; Surface du Seuil intérieur: 0 cm2; Surface de la Grille: 0 cm2; Volume de la Grille: 0 cm3
IFC_Pset_Matériaux - Seuil: Blanc trafic
IFC_Pset_Matériaux_1° MENUISERIE - Cadre externe: Blanc trafic; Verre: Transparent
Pset_WindowCommon - Reference: F[R] VV (..\IDEAL 5000 eko okna\) <aucun>
Name | In | OverallHeight (cm) = Hauteur (cm) | OverallWidth (cm) | __RECOGNIZE__, ID = IFC_Pset_Caractéristiques, ID | Numérotation | Numéro niveau | Titre niveau | Présent | Épaisseur extérieure (cm) | Épaisseur latérale gauche (cm) = Épaisseur latérale droite (cm) = Épiasseur latérale supérieure (cm) | Épaisseur diagonale gauche (cm) = Épaisseur diagonale droite (cm) = Épaisseur diagonale inférieure (cm) = Épaisseur diagonale supérieure (cm) | Données | Appui intérieur (cm) | Décalage (cm) | Invertir (intérieur/extérieur) | Largeur (cm) | NIVEAU | delta (cm) | Surface 1re Menuiserie (cm2) | Surface Vitre 1re Menuiserie (cm2) | Surface du Cadre de la 1re Menuiserie (cm2) | Surface de l'Ouverture (cm2) | Surface de l'Ébrasement (cm2) | Surface du Seuil (cm2) | Volume du seuil (cm3) = Volume du seuil intérieur (cm3)
Fenêtre 528251 | Rez-de-Jardin | 105.4 | 151.095 | 528251 | 077 | 02 | Rez-de-Jardin | yes | 4 | 5 | 5 | [a : 40,00; b: 50,00; c: 50,00; d: 0,00] mm | 4 | -8 | yes | 140.904 | Rez-de-Jardin (Rez-de-Jardin 15545) | 286 | 15900 | 12800 | 3200 | 14900 | 97400 | 4600 | 10000
Fenêtre 526329 | Rez-de-Jardin | 141.195 | 144.02 | 526329 | 076 | 02 | Rez-de-Jardin | yes | 4 | 3 | 6 | [a : 40,00; b: 30,00; c: 60,00; d: 0,00] mm | 4.5 | -9.5 | yes | 144.02 | Rez-de-Jardin (Rez-de-Jardin 15545) | 125 | 20300 | 16800 | 3500 | 20300 | 128600 | 4700 | 10000
Fenêtre 528252 | Rez-de-Jardin | 105.4 | 150.008 | 528252 | 078 | 02 | Rez-de-Jardin | yes | 4 | 4 | 6 | [a : 40,00; b: 40,00; c: 60,00; d: 0,00] mm | 4 | -8 | yes | 141.92 | Rez-de-Jardin (Rez-de-Jardin 15545) | 286 | 15800 | 12700 | 3200 | 15000 | 100500 | 4600 | 10000
Fenêtre 956421 | Rez-de-Jardin | 104 | 168.943 | 956421 | 125 | 02 | Rez-de-Jardin | no | 0 | 0 | 0 |  | 4 | -8 | no | 168.943 | Rez-de-Jardin (Rez-de-Jardin 15545) | 287 | 17600 | 14200 | 3400 | 17600 | 0 | 5300 | 20000
Fenêtre 528257 | Rez-de-Jardin | 104 | 151.088 | 528257 | 080 | 02 | Rez-de-Jardin | yes | 4 | 5 | 5 | [a : 40,00; b: 50,00; c: 50,00; d: 0,00] mm | 4 | -8 | no | 140.896 | Rez-de-Jardin (Rez-de-Jardin 15545) | 287 | 15700 | 12600 | 3100 | 14700 | 6500 | 4500 | 10000
Fenêtre 528254 | Rez-de-Jardin | 136 | 142.605 | 528254 | 079 | 02 | Rez-de-Jardin | yes | 4 | 4 | 5 | [a : 40,00; b: 40,00; c: 50,00; d: 0,00] mm | 4.5 | -9.5 | no | 142.605 | Rez-de-Jardin (Rez-de-Jardin 15545) | 131 | 19400 | 15900 | 3500 | 19400 | 8200 | 4600 | 10000
Fenêtre 728241 | Rez-de-chaussée | 101.871 | 130.332 | 728241 | 108 | 03 | Rez-de-chaussée | yes | 6 | 7 | 0 | [a : 60,00; b: 70,00; c: 0,00; d: 0,00] mm | 4 | -8 | no | 130.332 | Rez-de-chaussée (Rez-de-chaussée 1047) | 0.0128504 | 13300 | 10400 | 2800 | 13300 | 6600 | 4200 | 10000
Fenêtre 728242 | Rez-de-chaussée | 102.685 | 149.039 | 728242 | 109 | 03 | Rez-de-chaussée | yes | 6 | 7 | 0 | [a : 60,00; b: 70,00; c: 0,00; d: 0,00] mm | 4 | -8 | no | 149.039 | Rez-de-chaussée (Rez-de-chaussée 1047) | 0.012856 | 15300 | 12200 | 3100 | 15300 | 6700 | 4800 | 10000

# IfcWindow: F[R] VV, Fenêtre 528261
In: Rez-de-Jardin
Type - OperationType: SINGLE_PANEL; ParameterTakesPrecedence: yes; Sizeable: no; Material: Transparent, Blanc trafic, Brèche oniciata
Type - IfcWindowLiningProperties - LiningDepth: 7 cm; LiningThickness: 6.5 cm
Type - IfcWindowPanelProperties - OperationType: FIXEDCASEMENT; PanelPosition: MIDDLE; FrameDepth: 7 cm; FrameThickness: 6.5 cm
Description: Fenêtre; OverallHeight: 105 cm; OverallWidth: 171.5 cm
__RECOGNIZE__ - ID: 528261; TPLG: 101; TPLG_OD: 9004; GENERATE: 1
CTLG_EXTERNAL_LINK - 0, DocType: 3; 0, Tag: 100; 0, Crc: 374824113; 1, DocType: 2; 1, Tag: 0; 1, Crc: -746779066; 2, DocType: 2; 2, Tag: 15; 2, Crc: 1141262141; 3, DocType: 2; 3, Tag: 102; 3, Crc: -1731763687; 4, DocType: 2; 4, Tag: 104; 4, Crc: -623492449
IFC_PSET_PolygonOffset - polygonOffsetFactor: 2; polygonOffsetUnits: 2
IFC_Pset_Caractéristiques - ID: 528261; Numérotation: 081; Numéro niveau: 02; Titre niveau: Rez-de-Jardin; Modèle 1re menuiserie: F[R] VV
IFC_Pset_Géométrie_Allège - Hauteur: 0 cm; Stratigraphie: ...; Épaisseur: 0 cm
IFC_Pset_Géométrie_Ébrasement - Présent: no; Côté supérieur: no; Côté INFÉRIEUR: no; Épaisseur extérieure: 0 cm; Épaisseur latérale gauche: 0 cm; Épaisseur latérale droite: 0 cm; Épiasseur latérale supérieure: 0 cm; Épaisseur diagonale gauche: 0 cm; Épaisseur diagonale droite: 0 cm; Épaisseur diagonale inférieure: 0 cm; Épaisseur diagonale supérieure: 0 cm; Épaisseur intérieur: 0 cm
IFC_Pset_Géométrie_Seuil - Type: Unique; Épaisseur: 3 cm; Épaisseur interne: 3 cm; Décalage séparation: 0 cm; Appui extérieur: 0 cm; Appui intérieur: 5 cm; Côté latéral externe: 5 cm; Côté latéral interne: 5 cm
IFC_Pset_Géométrie_Chambranle - Position: Aucun; Épaisseur Chambranle intérieur: 0 cm; Longueur Chambranle intérieur: 0 cm; Superposition Chambranle intérieur: 0 cm; Épaisseur Intrados: 0 cm; Épaisseur Chambranle extérieur: 0 cm; Largeur Chambranle extérieur: 0 cm; Superposition Chambranle extérieur: 0 cm; Épaisseur Intrados extérieur: 0 cm
IFC_Pset_Géométrie_CORNICHE depuis profil - Position: Aucune; sets with these values: 2
IFC_Pset_Géométrie_CORNICHE Extérieure à partir d'un profil - Décalage: 0; Angle: 0 deg; Symétrie: no; Fermer: no; sets with these values: 2
IFC_Pset_Géométrie_BASE Extérieure à partir d'un profil - Angle: 0 deg; Symétrie: no; Côté: 0 cm; sets with these values: 2
IFC_Pset_Géométrie_1° MENUISERIE - Position: Centre; Décalage: -8 cm
IFC_Pset_Géométrie_2° MENUISERIE - Décalage: 0 cm
IFC_Pset_Géométrie - Côté extérieur: 1; Invertir (dte/gche): no; Invertir (intérieur/extérieur): yes; Largeur: 171.5 cm; Hauteur: 105 cm; Hauteur 2: 0 cm; Rayon Arc: 0 cm; Rayon Cercle: 0 cm; Demi-axe horizontal: 0 cm; Demi-axe vertical: 0 cm
IFC_Pset_Géométrie_GRILLE - décalage: 0 cm; Offset latéral: 0 cm; Décalage supérieur: 0 cm; Décalage inférieur: 0 cm; Nombre accrochages latéraux: 0; Nombre d'accrochages supérieurs: 0; Nombre accrochages inférieurs: 0
IFC_Pset_Système de Référence Altimétrique_INFÉRIEUR - NIVEAU: Rez-de-Jardin (Rez-de-Jardin 15545); delta: 286 cm; sous Niveau: <aucun>
IFC_Pset_Données Métré - Surface 1re Menuiserie: 18000 cm2; Surface Vitre 1re Menuiserie: 14600 cm2; Surface du Cadre de la 1re Menuiserie: 3400 cm2; Surface 2e Menuiserie: 0 cm2; Surface Vitre 2e Menuiserie: 0 cm2; Surface du Cadre de la 2ème Menuiserie: 0 cm2; Surface de l'Ouverture: 18000 cm2; Surface de l'Ébrasement: 0 cm2; Surface du Seuil: 5400 cm2; Surface du Seuil intérieur: 0 cm2; Volume du seuil: 20000 cm3; Volume du seuil intérieur: 20000 cm3; Surface de la Grille: 0 cm2; Volume de la Grille: 0 cm3
IFC_Pset_Matériaux - Seuil: Brèche oniciata
IFC_Pset_Matériaux_1° MENUISERIE - Cadre externe: Blanc trafic; Verre: Transparent
Pset_WindowCommon - Reference: F[R] VV (..\IDEAL 5000 eko okna\) <aucun>

# IfcWindow: F[R] VV, Fenêtre 531068
In: Rez-de-Jardin
Type - OperationType: SINGLE_PANEL; ParameterTakesPrecedence: yes; Sizeable: no; Material: Transparent, Blanc trafic, Béton (01)
Type - IfcWindowLiningProperties - LiningDepth: 7 cm; LiningThickness: 6.5 cm
Type - IfcWindowPanelProperties - OperationType: FIXEDCASEMENT; PanelPosition: MIDDLE; FrameDepth: 7 cm; FrameThickness: 6.5 cm
Description: Fenêtre; OverallHeight: 104 cm; OverallWidth: 171.472 cm
__RECOGNIZE__ - ID: 531068; TPLG: 101; TPLG_OD: 9004; GENERATE: 1
CTLG_EXTERNAL_LINK - 0, DocType: 3; 0, Tag: 100; 0, Crc: 374824113; 1, DocType: 2; 1, Tag: 0; 1, Crc: -746779066; 2, DocType: 2; 2, Tag: 15; 2, Crc: -1434640612; 3, DocType: 2; 3, Tag: 102; 3, Crc: -1731763687; 4, DocType: 2; 4, Tag: 104; 4, Crc: -623492449
IFC_PSET_PolygonOffset - polygonOffsetFactor: 2; polygonOffsetUnits: 2
IFC_Pset_Caractéristiques - ID: 531068; Numérotation: 082; Numéro niveau: 02; Titre niveau: Rez-de-Jardin; Modèle 1re menuiserie: F[R] VV
IFC_Pset_Géométrie_Allège - Hauteur: 0 cm; Stratigraphie: ...; Épaisseur: 0 cm
IFC_Pset_Géométrie_Ébrasement - Présent: no; Côté supérieur: no; Côté INFÉRIEUR: no; Épaisseur extérieure: 0 cm; Épaisseur latérale gauche: 0 cm; Épaisseur latérale droite: 0 cm; Épiasseur latérale supérieure: 0 cm; Épaisseur diagonale gauche: 0 cm; Épaisseur diagonale droite: 0 cm; Épaisseur diagonale inférieure: 0 cm; Épaisseur diagonale supérieure: 0 cm; Épaisseur intérieur: 0 cm
IFC_Pset_Géométrie_Seuil - Type: Unique; Épaisseur: 3 cm; Épaisseur interne: 3 cm; Décalage séparation: 0 cm; Appui extérieur: 5 cm; Appui intérieur: 0 cm; Côté latéral externe: 0 cm; Côté latéral interne: 0 cm
IFC_Pset_Géométrie_Chambranle - Position: Aucun; Épaisseur Chambranle intérieur: 0 cm; Longueur Chambranle intérieur: 0 cm; Superposition Chambranle intérieur: 0 cm; Épaisseur Intrados: 0 cm; Épaisseur Chambranle extérieur: 0 cm; Largeur Chambranle extérieur: 0 cm; Superposition Chambranle extérieur: 0 cm; Épaisseur Intrados extérieur: 0 cm
IFC_Pset_Géométrie_CORNICHE depuis profil - Position: Aucune; sets with these values: 2
IFC_Pset_Géométrie_CORNICHE Extérieure à partir d'un profil - Décalage: 0; Angle: 0 deg; Symétrie: no; Fermer: no; sets with these values: 2
IFC_Pset_Géométrie_BASE Extérieure à partir d'un profil - Angle: 0 deg; Symétrie: no; Côté: 0 cm; sets with these values: 2
IFC_Pset_Géométrie_1° MENUISERIE - Position: Centre; Décalage: 0 cm
IFC_Pset_Géométrie_2° MENUISERIE - Décalage: 0 cm
IFC_Pset_Géométrie - Côté extérieur: 1; Invertir (dte/gche): no; Invertir (intérieur/extérieur): yes; Largeur: 171.472 cm; Hauteur: 104 cm; Hauteur 2: 0 cm; Rayon Arc: 0 cm; Rayon Cercle: 0 cm; Demi-axe horizontal: 0 cm; Demi-axe vertical: 0 cm
IFC_Pset_Géométrie_GRILLE - décalage: 0 cm; Offset latéral: 0 cm; Décalage supérieur: 0 cm; Décalage inférieur: 0 cm; Nombre accrochages latéraux: 0; Nombre d'accrochages supérieurs: 0; Nombre accrochages inférieurs: 0
IFC_Pset_Système de Référence Altimétrique_INFÉRIEUR - NIVEAU: Rez-de-Jardin (Rez-de-Jardin 15545); delta: 287 cm; sous Niveau: <aucun>
IFC_Pset_Données Métré - Surface 1re Menuiserie: 17800 cm2; Surface Vitre 1re Menuiserie: 14400 cm2; Surface du Cadre de la 1re Menuiserie: 3400 cm2; Surface 2e Menuiserie: 0 cm2; Surface Vitre 2e Menuiserie: 0 cm2; Surface du Cadre de la 2ème Menuiserie: 0 cm2; Surface de l'Ouverture: 17800 cm2; Surface de l'Ébrasement: 0 cm2; Surface du Seuil: 2400 cm2; Surface du Seuil intérieur: 0 cm2; Volume du seuil: 10000 cm3; Volume du seuil intérieur: 10000 cm3; Surface de la Grille: 0 cm2; Volume de la Grille: 0 cm3
IFC_Pset_Matériaux - Seuil: Béton (01)
IFC_Pset_Matériaux_1° MENUISERIE - Cadre externe: Blanc trafic; Verre: Transparent
Pset_WindowCommon - Reference: F[R] VV (..\IDEAL 5000 eko okna\) <aucun>

# IfcWindow: F[R] VV (3)
Type - OperationType: SINGLE_PANEL; ParameterTakesPrecedence: yes; Sizeable: no; Material: Transparent, Sapin blanc
Type - IfcWindowLiningProperties - LiningDepth: 7 cm; LiningThickness: 6.5 cm
Type - IfcWindowPanelProperties - OperationType: FIXEDCASEMENT; PanelPosition: MIDDLE; FrameDepth: 7 cm; FrameThickness: 6.5 cm
Description: Fenêtre
__RECOGNIZE__ - TPLG: 101; TPLG_OD: 9004; GENERATE: 1
CTLG_EXTERNAL_LINK - 0, DocType: 3; 0, Tag: 100; 0, Crc: 374824113; 1, DocType: 2; 1, Tag: 0; 1, Crc: -746779066; 2, DocType: 2; 2, Tag: 102; 2, Crc: -1637103103; 3, DocType: 2; 3, Tag: 104; 3, Crc: -623492449
IFC_PSET_PolygonOffset - polygonOffsetFactor: 2; polygonOffsetUnits: 2
IFC_Pset_Caractéristiques - Modèle 1re menuiserie: F[R] VV
IFC_Pset_Géométrie_Allège - Hauteur: 0 cm; Stratigraphie: ...; Épaisseur: 0 cm
IFC_Pset_Géométrie_Ébrasement - Présent: yes; Côté supérieur: no; Épaisseur extérieure: 5 cm; Épaisseur latérale gauche: 5 cm; Épaisseur latérale droite: 5 cm; Épiasseur latérale supérieure: 5 cm; Épaisseur diagonale gauche: 0 cm; Épaisseur diagonale droite: 0 cm; Épaisseur diagonale supérieure: 0 cm; Épaisseur intérieur: 0 cm; Données: [a : 50,00; b: 50,00; c: 0,00; d: 0,00] mm
IFC_Pset_Géométrie_Seuil - Type: Aucun; Épaisseur: 0 cm; Épaisseur interne: 0 cm; Décalage séparation: 0 cm; Appui extérieur: 0 cm; Appui intérieur: 0 cm; Côté latéral externe: 0 cm; Côté latéral interne: 0 cm
IFC_Pset_Géométrie_Chambranle - Position: Aucun; Épaisseur Chambranle intérieur: 0 cm; Longueur Chambranle intérieur: 0 cm; Superposition Chambranle intérieur: 0 cm; Épaisseur Intrados: 0 cm; Épaisseur Chambranle extérieur: 0 cm; Largeur Chambranle extérieur: 0 cm; Superposition Chambranle extérieur: 0 cm; Épaisseur Intrados extérieur: 0 cm
IFC_Pset_Géométrie_CORNICHE depuis profil - Position: Aucune; sets with these values: 2
IFC_Pset_Géométrie_CORNICHE Extérieure à partir d'un profil - Décalage: 0; Angle: 0 deg; Symétrie: no; Fermer: no; sets with these values: 2
IFC_Pset_Géométrie_BASE Extérieure à partir d'un profil - Angle: 0 deg; Symétrie: no; Côté: 0 cm; sets with these values: 2
IFC_Pset_Géométrie_2° MENUISERIE - Décalage: 0 cm
IFC_Pset_Géométrie - Côté extérieur: 0; Invertir (dte/gche): no; Invertir (intérieur/extérieur): no; Hauteur 2: 0 cm; Rayon Arc: 0 cm; Rayon Cercle: 0 cm; Demi-axe horizontal: 0 cm; Demi-axe vertical: 0 cm
IFC_Pset_Géométrie_GRILLE - décalage: 0 cm; Offset latéral: 0 cm; Décalage supérieur: 0 cm; Décalage inférieur: 0 cm; Nombre accrochages latéraux: 0; Nombre d'accrochages supérieurs: 0; Nombre accrochages inférieurs: 0
IFC_Pset_Système de Référence Altimétrique_INFÉRIEUR - sous Niveau: <aucun>
IFC_Pset_Données Métré - Surface 2e Menuiserie: 0 cm2; Surface Vitre 2e Menuiserie: 0 cm2; Surface du Cadre de la 2ème Menuiserie: 0 cm2; Surface du Seuil: 0 cm2; Surface du Seuil intérieur: 0 cm2; Volume du seuil: 0 cm3; Volume du seuil intérieur: 0 cm3; Surface de la Grille: 0 cm2; Volume de la Grille: 0 cm3
IFC_Pset_Matériaux_1° MENUISERIE - Cadre externe: Sapin blanc; Verre: Transparent
Pset_WindowCommon - Reference: F[R] VV (..\IDEAL 5000 eko okna\) <aucun>
Name | In | OverallHeight (cm) | OverallWidth (cm) | __RECOGNIZE__, ID = IFC_Pset_Caractéristiques, ID | Numérotation | Numéro niveau | Titre niveau | Côté INFÉRIEUR | Épaisseur diagonale inférieure (cm) | Position | Décalage (cm) | Largeur (cm) | Hauteur (cm) | NIVEAU | delta (cm) | Surface 1re Menuiserie (cm2) | Surface Vitre 1re Menuiserie (cm2) | Surface du Cadre de la 1re Menuiserie (cm2) | Surface de l'Ouverture (cm2) | Surface de l'Ébrasement (cm2)
Fenêtre 531667 | Rez-de-chaussée | 333 | 170.275 | 531667 | 087 | 03 | Rez-de-chaussée | no | 0 | Extérieur | 0 | 170.275 | 333 | Rez-de-chaussée (Rez-de-chaussée 1047) | 119.8 | 56700 | 50300 | 6400 | 56700 | 20600
Fenêtre 533290 | Niveau 1 | 360 | 169.083 | 533290 | 098 | 04 | Niveau 1 | no | 0 | Extérieur | 0 | 169.083 | 360 | Niveau 1 (Niveau 1 2343) | -7 | 60900 | 54200 | 6700 | 60900 | 22500
Fenêtre 1525424 | Mezzanine | 99.0245 | 171.196 | 1525424 | 126 | 06 | Mezzanine | yes | 3.5 | Centre | -8 | 161.196 | 99 | Mezzanine (Mezzanine 49003) | 10 | 17000 | 13600 | 3300 | 16000 | 10800

# IfcWindow: Fn 1 montant fixe 2 vitres ép 90 (2)
In: Niveau 1
Type - OperationType: TRIPLE_PANEL_HORIZONTAL; ParameterTakesPrecedence: yes; Sizeable: no; Material: Bleu france, Transparent
Type - IfcWindowLiningProperties - LiningDepth: 9 cm; LiningThickness: 8 cm; TransomThickness: 0.1 cm; FirstTransomOffset: 0.346032; SecondTransomOffset: 0.653968
Type - IfcWindowPanelProperties - OperationType: FIXEDCASEMENT; PanelPosition: TOP; FrameDepth: 6 cm; FrameThickness: 3 cm
Description: Fenêtre
__RECOGNIZE__ - TPLG: 101; TPLG_OD: 9004; GENERATE: 1
CTLG_EXTERNAL_LINK - 0, DocType: 3; 0, Tag: 100; 0, Crc: -519161385; 1, DocType: 2; 1, Tag: 0; 1, Crc: -746779066; 2, DocType: 2; 2, Tag: 102; 2, Crc: 1181025438; 3, DocType: 2; 3, Tag: 104; 3, Crc: -623492449
IFC_PSET_PolygonOffset - polygonOffsetFactor: 2; polygonOffsetUnits: 2
IFC_Pset_Caractéristiques - Numéro niveau: 04; Titre niveau: Niveau 1; Modèle 1re menuiserie: Fn 1 montant fixe 2 vitres ép 90
IFC_Pset_Géométrie_Allège - Hauteur: 0 cm; Stratigraphie: ...; Épaisseur: 0 cm
IFC_Pset_Géométrie_Ébrasement - Présent: no; Côté supérieur: no; Côté INFÉRIEUR: no; Épaisseur extérieure: 0 cm; Épaisseur latérale gauche: 0 cm; Épaisseur latérale droite: 0 cm; Épiasseur latérale supérieure: 0 cm; Épaisseur diagonale gauche: 0 cm; Épaisseur diagonale droite: 0 cm; Épaisseur diagonale inférieure: 0 cm; Épaisseur diagonale supérieure: 0 cm; Épaisseur intérieur: 0 cm
IFC_Pset_Géométrie_Seuil - Type: Aucun; Épaisseur: 0 cm; Épaisseur interne: 0 cm; Décalage séparation: 0 cm; Appui extérieur: 0 cm; Appui intérieur: 0 cm; Côté latéral externe: 0 cm; Côté latéral interne: 0 cm
IFC_Pset_Géométrie_Chambranle - Position: Aucun; Épaisseur Chambranle intérieur: 0 cm; Longueur Chambranle intérieur: 0 cm; Superposition Chambranle intérieur: 0 cm; Épaisseur Intrados: 0 cm; Épaisseur Chambranle extérieur: 0 cm; Largeur Chambranle extérieur: 0 cm; Superposition Chambranle extérieur: 0 cm; Épaisseur Intrados extérieur: 0 cm
IFC_Pset_Géométrie_CORNICHE depuis profil - Position: Aucune; sets with these values: 2
IFC_Pset_Géométrie_CORNICHE Extérieure à partir d'un profil - Décalage: 0; Angle: 0 deg; Symétrie: no; Fermer: no; sets with these values: 2
IFC_Pset_Géométrie_BASE Extérieure à partir d'un profil - Angle: 0 deg; Symétrie: no; Côté: 0 cm; sets with these values: 2
IFC_Pset_Géométrie_1° MENUISERIE - Position: Centre; Décalage: 0 cm
IFC_Pset_Géométrie_2° MENUISERIE - Décalage: 0 cm
IFC_Pset_Géométrie - Côté extérieur: 0; Invertir (dte/gche): no; Invertir (intérieur/extérieur): no; Hauteur 2: 0 cm; Rayon Arc: 0 cm; Rayon Cercle: 0 cm; Demi-axe horizontal: 0 cm; Demi-axe vertical: 0 cm
IFC_Pset_Géométrie_GRILLE - décalage: 0 cm; Offset latéral: 0 cm; Décalage supérieur: 0 cm; Décalage inférieur: 0 cm; Nombre accrochages latéraux: 0; Nombre d'accrochages supérieurs: 0; Nombre accrochages inférieurs: 0
IFC_Pset_Système de Référence Altimétrique_INFÉRIEUR - NIVEAU: Niveau 1 (Niveau 1 2343); delta: 0.0128504 cm; sous Niveau: <aucun>
IFC_Pset_Données Métré - Surface 2e Menuiserie: 0 cm2; Surface Vitre 2e Menuiserie: 0 cm2; Surface du Cadre de la 2ème Menuiserie: 0 cm2; Surface de l'Ébrasement: 0 cm2; Surface du Seuil: 0 cm2; Surface du Seuil intérieur: 0 cm2; Volume du seuil: 0 cm3; Volume du seuil intérieur: 0 cm3; Surface de la Grille: 0 cm2; Volume de la Grille: 0 cm3
IFC_Pset_Matériaux_1° MENUISERIE - Cadre externe: Bleu france; Verre: Transparent
Pset_WindowCommon - Reference: Fn 1 montant fixe 2 vitres ép 90 (..\Menuiserie classique\Fenêtre et Balcon\) <aucun>
Name | OverallHeight (cm) = Hauteur (cm) | OverallWidth (cm) = Largeur (cm) | __RECOGNIZE__, ID = IFC_Pset_Caractéristiques, ID | Numérotation | Surface 1re Menuiserie (cm2) = Surface de l'Ouverture (cm2) | Surface Vitre 1re Menuiserie (cm2) | Surface du Cadre de la 1re Menuiserie (cm2)
Fenêtre 105267 | 210 | 85.5626 | 105267 | 039 | 18000 | 11200 | 6800
Fenêtre 104770 | 207 | 85.6824 | 104770 | 038 | 17700 | 11000 | 6700

# IfcWindow: Fn 1 montant fixe 2 vitres ép 90 (32)
Type - OperationType: TRIPLE_PANEL_HORIZONTAL; ParameterTakesPrecedence: yes; Sizeable: no; Material: Transparent, Blanc trafic
Type - IfcWindowLiningProperties - LiningDepth: 9 cm; LiningThickness: 8 cm; TransomThickness: 0.1 cm; FirstTransomOffset: 0.341341; SecondTransomOffset: 0.658659
Type - IfcWindowPanelProperties - OperationType: FIXEDCASEMENT; PanelPosition: TOP; FrameDepth: 6 cm; FrameThickness: 3 cm
Description: Fenêtre
__RECOGNIZE__ - TPLG: 101; TPLG_OD: 9004; GENERATE: 1
CTLG_EXTERNAL_LINK - 0, DocType: 3; 0, Tag: 100; 0, Crc: -519161385; 1, DocType: 2; 1, Tag: 0; 1, Crc: -746779066; 2, DocType: 2; 2, Tag: 102; 2, Crc: -848491367; 3, DocType: 2; 3, Tag: 104; 3, Crc: -623492449
IFC_PSET_PolygonOffset - polygonOffsetFactor: 2; polygonOffsetUnits: 2
IFC_Pset_Caractéristiques - Modèle 1re menuiserie: Fn 1 montant fixe 2 vitres ép 90
IFC_Pset_Géométrie_Allège - Hauteur: 0 cm; Stratigraphie: ...; Épaisseur: 0 cm
IFC_Pset_Géométrie_Ébrasement - Côté supérieur: no; Côté INFÉRIEUR: no; Épaisseur intérieur: 0 cm
IFC_Pset_Géométrie_Seuil - Type: Aucun; Épaisseur: 0 cm; Épaisseur interne: 0 cm; Décalage séparation: 0 cm; Appui extérieur: 0 cm; Appui intérieur: 0 cm; Côté latéral externe: 0 cm; Côté latéral interne: 0 cm
IFC_Pset_Géométrie_Chambranle - Position: Aucun; Épaisseur Chambranle intérieur: 0 cm; Longueur Chambranle intérieur: 0 cm; Superposition Chambranle intérieur: 0 cm; Épaisseur Intrados: 0 cm; Épaisseur Chambranle extérieur: 0 cm; Largeur Chambranle extérieur: 0 cm; Superposition Chambranle extérieur: 0 cm; Épaisseur Intrados extérieur: 0 cm
IFC_Pset_Géométrie_CORNICHE depuis profil - Position: Aucune; sets with these values: 2
IFC_Pset_Géométrie_CORNICHE Extérieure à partir d'un profil - Décalage: 0; Angle: 0 deg; Symétrie: no; Fermer: no; sets with these values: 2
IFC_Pset_Géométrie_BASE Extérieure à partir d'un profil - Angle: 0 deg; Symétrie: no; Côté: 0 cm; sets with these values: 2
IFC_Pset_Géométrie_1° MENUISERIE - Position: Extérieur
IFC_Pset_Géométrie_2° MENUISERIE - Décalage: 0 cm
IFC_Pset_Géométrie - Invertir (dte/gche): no; Hauteur 2: 0 cm; Rayon Arc: 0 cm; Rayon Cercle: 0 cm; Demi-axe horizontal: 0 cm; Demi-axe vertical: 0 cm
IFC_Pset_Géométrie_GRILLE - décalage: 0 cm; Offset latéral: 0 cm; Décalage supérieur: 0 cm; Décalage inférieur: 0 cm; Nombre accrochages latéraux: 0; Nombre d'accrochages supérieurs: 0; Nombre accrochages inférieurs: 0
IFC_Pset_Système de Référence Altimétrique_INFÉRIEUR - sous Niveau: <aucun>
IFC_Pset_Données Métré - Surface 2e Menuiserie: 0 cm2; Surface Vitre 2e Menuiserie: 0 cm2; Surface du Cadre de la 2ème Menuiserie: 0 cm2; Surface du Seuil: 0 cm2; Surface du Seuil intérieur: 0 cm2; Volume du seuil: 0 cm3; Volume du seuil intérieur: 0 cm3; Surface de la Grille: 0 cm2; Volume de la Grille: 0 cm3
IFC_Pset_Matériaux_1° MENUISERIE - Cadre externe: Blanc trafic; Verre: Transparent
Pset_WindowCommon - Reference: Fn 1 montant fixe 2 vitres ép 90 (..\Menuiserie classique\Fenêtre et Balcon\) <aucun>
Name | In | OverallHeight (cm) = Hauteur (cm) | OverallWidth (cm) = Largeur (cm) | __RECOGNIZE__, ID = IFC_Pset_Caractéristiques, ID | Numérotation | Numéro niveau | Titre niveau | Présent | Épaisseur extérieure (cm) | Épaisseur latérale gauche (cm) = Épaisseur latérale droite (cm) = Épiasseur latérale supérieure (cm) | Épaisseur diagonale gauche (cm) = Épaisseur diagonale droite (cm) = Épaisseur diagonale inférieure (cm) = Épaisseur diagonale supérieure (cm) | Décalage (cm) | Côté extérieur | Invertir (intérieur/extérieur) | NIVEAU | delta (cm) | Surface 1re Menuiserie (cm2) = Surface de l'Ouverture (cm2) | Surface Vitre 1re Menuiserie (cm2) | Surface du Cadre de la 1re Menuiserie (cm2) | Surface de l'Ébrasement (cm2) | Données
Fenêtre 73505 | Rez-de-Jardin | 253.5 | 143.783 | 73505 | 018 | 02 | Rez-de-Jardin | no | 0 | 0 | 0 | -1.5 | 1 | no | Rez-de-Jardin (Rez-de-Jardin 15545) | 14 | 36400 | 26700 | 9700 | 0
Fenêtre 76237 | Rez-de-Jardin | 97 | 111.462 | 76237 | 025 | 02 | Rez-de-Jardin | no | 0 | 0 | 0 | 0 | 0 | no | Rez-de-Jardin (Rez-de-Jardin 15545) | 142.337 | 10800 | 5600 | 5200 | 0
Fenêtre 531069 | Rez-de-chaussée | 333 | 135.105 | 531069 | 083 | 03 | Rez-de-chaussée | yes | 6 | 5 | 5 | 0 | 0 | no | Rez-de-chaussée (Rez-de-chaussée 1047) | 119.8 | 45000 | 33800 | 11200 | 21700 | [a : 60,00; b: 50,00; c: 50,00; d: 0,00] mm
Fenêtre 519559 | Rez-de-chaussée | 333 | 132.592 | 519559 | 075 | 03 | Rez-de-chaussée | yes | 6 | 6 | 5 | 0 | 0 | no | Rez-de-chaussée (Rez-de-chaussée 1047) | 119.8 | 44200 | 33100 | 11100 | 23000 | [a : 60,00; b: 60,00; c: 50,00; d: 0,00] mm
Fenêtre 531871 | Rez-de-chaussée | 333 | 139.073 | 531871 | 088 | 03 | Rez-de-chaussée | yes | 6 | 6 | 5 | 0 | 0 | no | Rez-de-chaussée (Rez-de-chaussée 1047) | 119.8 | 46300 | 35000 | 11300 | 21700 | [a : 60,00; b: 60,00; c: 50,00; d: 0,00] mm
Fenêtre 531532 | Rez-de-chaussée | 333 | 141.342 | 531532 | 085 | 03 | Rez-de-chaussée | yes | 6 | 5 | 5 | 0 | 0 | no | Rez-de-chaussée (Rez-de-chaussée 1047) | 119.8 | 47100 | 35700 | 11400 | 21100 | [a : 60,00; b: 50,00; c: 50,00; d: 0,00] mm
Fenêtre 531666 | Rez-de-chaussée | 333 | 161.871 | 531666 | 086 | 03 | Rez-de-chaussée | yes | 5 | 5 | 0 | 0 | 0 | no | Rez-de-chaussée (Rez-de-chaussée 1047) | 119.8 | 53900 | 41800 | 12100 | 20600 | [a : 50,00; b: 50,00; c: 0,00; d: 0,00] mm
Fenêtre 531530 | Rez-de-chaussée | 333 | 141.389 | 531530 | 084 | 03 | Rez-de-chaussée | yes | 6 | 5 | 5 | 0 | 0 | no | Rez-de-chaussée (Rez-de-chaussée 1047) | 119.8 | 47100 | 35700 | 11400 | 21100 | [a : 60,00; b: 50,00; c: 50,00; d: 0,00] mm
Fenêtre 531872 | Rez-de-chaussée | 333 | 139.492 | 531872 | 089 | 03 | Rez-de-chaussée | yes | 6 | 6 | 5 | 0 | 0 | no | Rez-de-chaussée (Rez-de-chaussée 1047) | 119.8 | 46500 | 35100 | 11300 | 21700 | [a : 60,00; b: 60,00; c: 50,00; d: 0,00] mm
Fenêtre 531873 | Rez-de-chaussée | 333 | 159.905 | 531873 | 090 | 03 | Rez-de-chaussée | yes | 4 | 6 | 0 | 0 | 0 | no | Rez-de-chaussée (Rez-de-chaussée 1047) | 119.8 | 53200 | 41200 | 12000 | 21300 | [a : 40,00; b: 60,00; c: 0,00; d: 0,00] mm
Fenêtre 728246 | Rez-de-chaussée | 331.675 | 144.325 | 728246 | 111 | 03 | Rez-de-chaussée | no | 0 | 0 | 0 | 0 | 0 | no | Rez-de-chaussée (Rez-de-chaussée 1047) | 120 | 47900 | 36400 | 11500 | 0
Fenêtre 728245 | Rez-de-chaussée | 325.912 | 162.995 | 728245 | 110 | 03 | Rez-de-chaussée | no | 0 | 0 | 0 | 0 | 0 | no | Rez-de-chaussée (Rez-de-chaussée 1047) | 122.992 | 53100 | 41200 | 12000 | 0
Fenêtre 955884 | Rez-de-chaussée | 475 | 97.6543 | 955884 | 123 | 03 | Rez-de-chaussée | no | 0 | 0 | 0 | 0 | 0 | no | Rez-de-chaussée (Rez-de-chaussée 1047) | 290 | 46400 | 33400 | 13000 | 0
Fenêtre 766479 | Rez-de-chaussée | 475 | 99.0416 | 766479 | 116 | 03 | Rez-de-chaussée | no | 0 | 0 | 0 | 0 | 0 | no | Rez-de-chaussée (Rez-de-chaussée 1047) | 290 | 47000 | 34000 | 13100 | 0
Fenêtre 532667 | Niveau 1 | 360 | 133.051 | 532667 | 093 | 04 | Niveau 1 | yes | 4 | 5 | 5 | 0 | 0 | no | Niveau 1 (Niveau 1 2343) | -7 | 47900 | 36200 | 11700 | 22700 | [a : 40,00; b: 50,00; c: 50,00; d: 0,00] mm
Fenêtre 532665 | Niveau 1 | 360 | 138.717 | 532665 | 092 | 04 | Niveau 1 | yes | 6 | 6 | 5 | 0 | 0 | no | Niveau 1 (Niveau 1 2343) | -7 | 49900 | 38000 | 11900 | 23500 | [a : 60,00; b: 60,00; c: 50,00; d: 0,00] mm
Fenêtre 532669 | Niveau 1 | 360 | 135.737 | 532669 | 095 | 04 | Niveau 1 | yes | 6 | 6 | 7 | 0 | 0 | no | Niveau 1 (Niveau 1 2343) | -7 | 48900 | 37100 | 11800 | 23900 | [a : 60,00; b: 60,00; c: 70,00; d: 0,00] mm
Fenêtre 532668 | Niveau 1 | 360 | 134.931 | 532668 | 094 | 04 | Niveau 1 | yes | 5 | 6 | 4 | 0 | 0 | no | Niveau 1 (Niveau 1 2343) | -7 | 48600 | 36800 | 11800 | 24000 | [a : 50,00; b: 60,00; c: 40,00; d: 0,00] mm
Fenêtre 532664 | Niveau 1 | 360 | 137.774 | 532664 | 091 | 04 | Niveau 1 | yes | 6 | 6 | 5 | 0 | 0 | no | Niveau 1 (Niveau 1 2343) | -6 | 49600 | 37700 | 11900 | 23500 | [a : 60,00; b: 60,00; c: 50,00; d: 0,00] mm
Fenêtre 532670 | Niveau 1 | 360 | 138.952 | 532670 | 096 | 04 | Niveau 1 | yes | 6 | 6 | 5 | 0 | 0 | no | Niveau 1 (Niveau 1 2343) | -7 | 50000 | 38100 | 11900 | 23500 | [a : 60,00; b: 60,00; c: 50,00; d: 0,00] mm
Fenêtre 532671 | Niveau 1 | 360 | 160.514 | 532671 | 097 | 04 | Niveau 1 | yes | 6 | 6 | 0 | 0 | 0 | no | Niveau 1 (Niveau 1 2343) | -7 | 57800 | 45200 | 12600 | 23000 | [a : 60,00; b: 60,00; c: 0,00; d: 0,00] mm
Fenêtre 728287 | Niveau 1 | 355 | 144.325 | 728287 | 112 | 04 | Niveau 1 | no | 0 | 0 | 0 | 0 | 1 | no | Niveau 1 (Niveau 1 2343) | -5 | 51200 | 39300 | 12000 | 0
Fenêtre 956363 | Niveau 1 | 360 | 162.958 | 956363 | 124 | 04 | Niveau 1 | yes | 5 | 3 | 1.5 | 0 | 0 | yes | Niveau 1 (Niveau 1 2343) | -6 | 58700 | 46000 | 12700 | 20900 | [a : 50,00; b: 30,00; c: 15,00; d: 0,00] mm
Fenêtre 551106 | Niveau 2 | 218 | 134.377 | 551106 | 099 | 05 | Niveau 2 | yes | 5 | 5 | 4.5 | 0 | 0 | no | Niveau 2 (Niveau 2 13545) | 7.86038e-12 | 29300 | 20700 | 8600 | 13700 | [a : 50,00; b: 50,00; c: 45,00; d: 0,00] mm
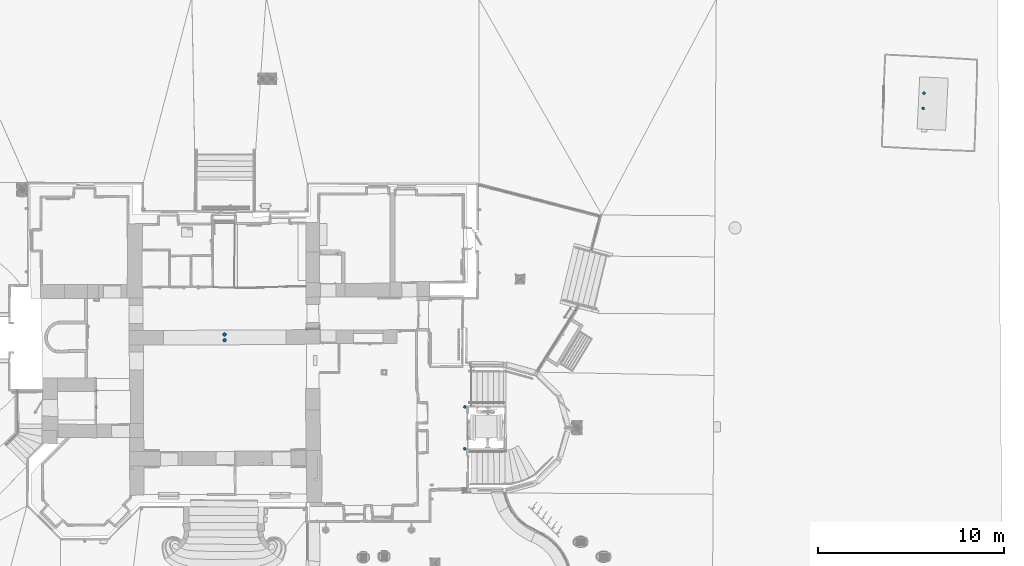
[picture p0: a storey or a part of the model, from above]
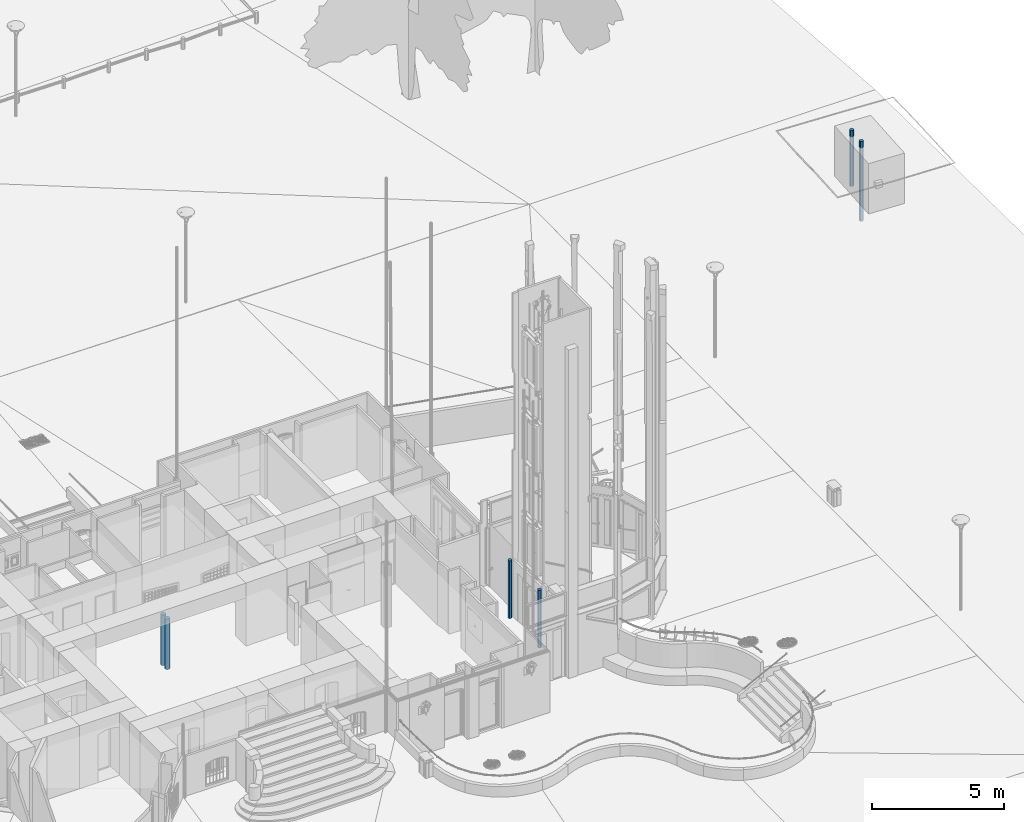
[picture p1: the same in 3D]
Properties of the parts of a building model (IFC2X3), part 37 of 37

# IfcWindow: Fn 1 montant fixe 2 vitres ép 90 (32)
Name | In | OverallHeight (cm) = Hauteur (cm) | OverallWidth (cm) = Largeur (cm) | __RECOGNIZE__, ID = IFC_Pset_Caractéristiques, ID | Numérotation | Numéro niveau | Titre niveau | Présent | Épaisseur extérieure (cm) | Épaisseur latérale gauche (cm) = Épaisseur latérale droite (cm) = Épiasseur latérale supérieure (cm) | Épaisseur diagonale gauche (cm) = Épaisseur diagonale droite (cm) = Épaisseur diagonale inférieure (cm) = Épaisseur diagonale supérieure (cm) | Décalage (cm) | Côté extérieur | Invertir (intérieur/extérieur) | NIVEAU | delta (cm) | Surface 1re Menuiserie (cm2) = Surface de l'Ouverture (cm2) | Surface Vitre 1re Menuiserie (cm2) | Surface du Cadre de la 1re Menuiserie (cm2) | Surface de l'Ébrasement (cm2) | Données
Fenêtre 551112 | Niveau 2 | 218 | 143.69 | 551112 | 105 | 05 | Niveau 2 | yes | 5 | 5 | 4 | 0 | 0 | no | Niveau 2 (Niveau 2 13545) | 7.10543e-12 | 31300 | 22400 | 8900 | 13700 | [a : 50,00; b: 50,00; c: 40,00; d: 0,00] mm
Fenêtre 551108 | Niveau 2 | 218 | 139.024 | 551108 | 101 | 05 | Niveau 2 | yes | 5 | 5 | 5 | 0 | 0 | no | Niveau 2 (Niveau 2 13545) | 7.83817e-12 | 30300 | 21500 | 8800 | 13800 | [a : 50,00; b: 50,00; c: 50,00; d: 0,00] mm
Fenêtre 551107 | Niveau 2 | 218 | 135.461 | 551107 | 100 | 05 | Niveau 2 | yes | 5 | 5 | 5 | 0 | 0 | no | Niveau 2 (Niveau 2 13545) | 7.28306e-12 | 29500 | 20900 | 8700 | 13800 | [a : 50,00; b: 50,00; c: 50,00; d: 0,00] mm
Fenêtre 551113 | Niveau 2 | 218 | 141.25 | 551113 | 106 | 05 | Niveau 2 | yes | 5 | 5 | 4 | 0 | 0 | no | Niveau 2 (Niveau 2 13545) | 7.83817e-12 | 30800 | 21900 | 8900 | 13700 | [a : 50,00; b: 50,00; c: 40,00; d: 0,00] mm
Fenêtre 551114 | Niveau 2 | 218 | 161.196 | 551114 | 107 | 05 | Niveau 2 | yes | 5 | 5 | 0 | 0 | 0 | no | Niveau 2 (Niveau 2 13545) | 8.19345e-12 | 35100 | 25600 | 9500 | 13500 | [a : 50,00; b: 50,00; c: 0,00; d: 0,00] mm
Fenêtre 551111 | Niveau 2 | 218 | 168.283 | 551111 | 104 | 05 | Niveau 2 | yes | 5 | 5 | 0 | 0 | 0 | no | Niveau 2 (Niveau 2 13545) | 7.81597e-12 | 36700 | 26900 | 9800 | 13500 | [a : 50,00; b: 50,00; c: 0,00; d: 0,00] mm
Fenêtre 551110 | Niveau 2 | 218 | 162.091 | 551110 | 103 | 05 | Niveau 2 | yes | 5 | 5 | 0 | 0 | 0 | no | Niveau 2 (Niveau 2 13545) | 7.4607e-12 | 35300 | 25800 | 9600 | 13500 | [a : 50,00; b: 50,00; c: 0,00; d: 0,00] mm
Fenêtre 551109 | Niveau 2 | 218 | 136.22 | 551109 | 102 | 05 | Niveau 2 | yes | 5 | 7 | 5 | 0 | 0 | no | Niveau 2 (Niveau 2 13545) | 6.39488e-12 | 29700 | 21000 | 8700 | 14600 | [a : 50,00; b: 70,00; c: 50,00; d: 0,00] mm

# IfcWindow: Fn 1 montant fixe 2 vitres ép 90, Fenêtre 74089
In: Rez-de-Jardin
Type - OperationType: TRIPLE_PANEL_HORIZONTAL; ParameterTakesPrecedence: yes; Sizeable: no; Material: Transparent, Blanc trafic
Type - IfcWindowLiningProperties - LiningDepth: 9 cm; LiningThickness: 8 cm; TransomThickness: 0.1 cm; FirstTransomOffset: 0.384615; SecondTransomOffset: 0.615385
Type - IfcWindowPanelProperties - OperationType: FIXEDCASEMENT; PanelPosition: TOP; FrameDepth: 6 cm; FrameThickness: 3 cm
Description: Fenêtre; OverallHeight: 52 cm; OverallWidth: 54.717 cm
__RECOGNIZE__ - ID: 74089; TPLG: 101; TPLG_OD: 9004; GENERATE: 1
CTLG_EXTERNAL_LINK - 0, DocType: 3; 0, Tag: 100; 0, Crc: -519161385; 1, DocType: 2; 1, Tag: 0; 1, Crc: -746779066; 2, DocType: 2; 2, Tag: 102; 2, Crc: -848491367; 3, DocType: 2; 3, Tag: 104; 3, Crc: 353406826
IFC_PSET_PolygonOffset - polygonOffsetFactor: 2; polygonOffsetUnits: 2
IFC_Pset_Caractéristiques - ID: 74089; Numérotation: 021; Numéro niveau: 02; Titre niveau: Rez-de-Jardin; Modèle 1re menuiserie: Fn 1 montant fixe 2 vitres ép 90
IFC_Pset_Géométrie_Allège - Hauteur: 0 cm; Stratigraphie: ...; Épaisseur: 0 cm
IFC_Pset_Géométrie_Ébrasement - Présent: no; Côté supérieur: no; Côté INFÉRIEUR: no; Épaisseur extérieure: 0 cm; Épaisseur latérale gauche: 0 cm; Épaisseur latérale droite: 0 cm; Épiasseur latérale supérieure: 0 cm; Épaisseur diagonale gauche: 0 cm; Épaisseur diagonale droite: 0 cm; Épaisseur diagonale inférieure: 0 cm; Épaisseur diagonale supérieure: 0 cm; Épaisseur intérieur: 0 cm
IFC_Pset_Géométrie_Seuil - Type: Aucun; Épaisseur: 0 cm; Épaisseur interne: 0 cm; Décalage séparation: 0 cm; Appui extérieur: 0 cm; Appui intérieur: 0 cm; Côté latéral externe: 0 cm; Côté latéral interne: 0 cm
IFC_Pset_Géométrie_Chambranle - Position: Aucun; Épaisseur Chambranle intérieur: 0 cm; Longueur Chambranle intérieur: 0 cm; Superposition Chambranle intérieur: 0 cm; Épaisseur Intrados: 0 cm; Épaisseur Chambranle extérieur: 0 cm; Largeur Chambranle extérieur: 0 cm; Superposition Chambranle extérieur: 0 cm; Épaisseur Intrados extérieur: 0 cm
IFC_Pset_Géométrie_CORNICHE depuis profil - Position: Aucune; sets with these values: 2
IFC_Pset_Géométrie_CORNICHE Extérieure à partir d'un profil - Décalage: 0; Angle: 0 deg; Symétrie: no; Fermer: no; sets with these values: 2
IFC_Pset_Géométrie_BASE Extérieure à partir d'un profil - Angle: 0 deg; Symétrie: no; Côté: 0 cm; sets with these values: 2
IFC_Pset_Géométrie_1° MENUISERIE - Position: Extérieur; Décalage: 0 cm
IFC_Pset_Géométrie_2° MENUISERIE - Décalage: 0 cm
IFC_Pset_Géométrie - Côté extérieur: 0; Invertir (dte/gche): no; Invertir (intérieur/extérieur): no; Largeur: 54.717 cm; Hauteur: 52 cm; Hauteur 2: 0 cm; Rayon Arc: 0 cm; Rayon Cercle: 0 cm; Demi-axe horizontal: 0 cm; Demi-axe vertical: 0 cm
IFC_Pset_Géométrie_GRILLE - décalage: 0 cm; Offset latéral: 0 cm; Décalage supérieur: 0 cm; Décalage inférieur: 0 cm; Nombre accrochages latéraux: 0; Nombre d'accrochages supérieurs: 0; Nombre accrochages inférieurs: 0
IFC_Pset_Système de Référence Altimétrique_INFÉRIEUR - NIVEAU: Rez-de-Jardin (Rez-de-Jardin 15545); delta: 120.103 cm; sous Niveau: <aucun>
IFC_Pset_Données Métré - Surface 1re Menuiserie: 2800 cm2; Surface Vitre 1re Menuiserie: 600 cm2; Surface du Cadre de la 1re Menuiserie: 2300 cm2; Surface 2e Menuiserie: 0 cm2; Surface Vitre 2e Menuiserie: 0 cm2; Surface du Cadre de la 2ème Menuiserie: 0 cm2; Surface de l'Ouverture: 2800 cm2; Surface de l'Ébrasement: 0 cm2; Surface du Seuil: 0 cm2; Surface du Seuil intérieur: 0 cm2; Volume du seuil: 0 cm3; Volume du seuil intérieur: 0 cm3; Surface de la Grille: 0 cm2; Volume de la Grille: 0 cm3
IFC_Pset_Matériaux_1° MENUISERIE - Cadre externe: Blanc trafic; Verre: Transparent
Pset_WindowCommon - Reference: Fn 1 montant fixe 2 vitres ép 90 (..\Menuiserie classique\Fenêtre et Balcon\) <aucun>

# IfcWindow: Fn 1 montant fixe 2 vitres ép 90, Fenêtre 152114
In: Niveau 2
Type - OperationType: TRIPLE_PANEL_HORIZONTAL; ParameterTakesPrecedence: yes; Sizeable: no; Material: Transparent, Gris lumière
Type - IfcWindowLiningProperties - LiningDepth: 9 cm; LiningThickness: 8 cm; TransomThickness: 0.1 cm; FirstTransomOffset: 0.346801; SecondTransomOffset: 0.653199
Type - IfcWindowPanelProperties - OperationType: FIXEDCASEMENT; PanelPosition: TOP; FrameDepth: 6 cm; FrameThickness: 3 cm
Description: Fenêtre; OverallHeight: 198 cm; OverallWidth: 103.1 cm
__RECOGNIZE__ - ID: 152114; TPLG: 101; TPLG_OD: 9004; GENERATE: 1
CTLG_EXTERNAL_LINK - 0, DocType: 3; 0, Tag: 100; 0, Crc: -519161385; 1, DocType: 2; 1, Tag: 0; 1, Crc: -746779066; 2, DocType: 2; 2, Tag: 102; 2, Crc: 1059052754; 3, DocType: 2; 3, Tag: 104; 3, Crc: -623492449
IFC_PSET_PolygonOffset - polygonOffsetFactor: 2; polygonOffsetUnits: 2
IFC_Pset_Caractéristiques - ID: 152114; Numérotation: 053; Numéro niveau: 05; Titre niveau: Niveau 2; Modèle 1re menuiserie: Fn 1 montant fixe 2 vitres ép 90
IFC_Pset_Géométrie_Allège - Hauteur: 0 cm; Stratigraphie: ...; Épaisseur: 0 cm
IFC_Pset_Géométrie_Ébrasement - Présent: no; Côté supérieur: no; Côté INFÉRIEUR: no; Épaisseur extérieure: 0 cm; Épaisseur latérale gauche: 0 cm; Épaisseur latérale droite: 0 cm; Épiasseur latérale supérieure: 0 cm; Épaisseur diagonale gauche: 0 cm; Épaisseur diagonale droite: 0 cm; Épaisseur diagonale inférieure: 0 cm; Épaisseur diagonale supérieure: 0 cm; Épaisseur intérieur: 0 cm
IFC_Pset_Géométrie_Seuil - Type: Aucun; Épaisseur: 0 cm; Épaisseur interne: 0 cm; Décalage séparation: 0 cm; Appui extérieur: 0 cm; Appui intérieur: 0 cm; Côté latéral externe: 0 cm; Côté latéral interne: 0 cm
IFC_Pset_Géométrie_Chambranle - Position: Aucun; Épaisseur Chambranle intérieur: 0 cm; Longueur Chambranle intérieur: 0 cm; Superposition Chambranle intérieur: 0 cm; Épaisseur Intrados: 0 cm; Épaisseur Chambranle extérieur: 0 cm; Largeur Chambranle extérieur: 0 cm; Superposition Chambranle extérieur: 0 cm; Épaisseur Intrados extérieur: 0 cm
IFC_Pset_Géométrie_CORNICHE depuis profil - Position: Aucune; sets with these values: 2
IFC_Pset_Géométrie_CORNICHE Extérieure à partir d'un profil - Décalage: 0; Angle: 0 deg; Symétrie: no; Fermer: no; sets with these values: 2
IFC_Pset_Géométrie_BASE Extérieure à partir d'un profil - Angle: 0 deg; Symétrie: no; Côté: 0 cm; sets with these values: 2
IFC_Pset_Géométrie_1° MENUISERIE - Position: Centre; Décalage: 0 cm
IFC_Pset_Géométrie_2° MENUISERIE - Décalage: 0 cm
IFC_Pset_Géométrie - Côté extérieur: 1; Invertir (dte/gche): no; Invertir (intérieur/extérieur): no; Largeur: 103.1 cm; Hauteur: 198 cm; Hauteur 2: 0 cm; Rayon Arc: 0 cm; Rayon Cercle: 0 cm; Demi-axe horizontal: 0 cm; Demi-axe vertical: 0 cm
IFC_Pset_Géométrie_GRILLE - décalage: 0 cm; Offset latéral: 0 cm; Décalage supérieur: 0 cm; Décalage inférieur: 0 cm; Nombre accrochages latéraux: 0; Nombre d'accrochages supérieurs: 0; Nombre accrochages inférieurs: 0
IFC_Pset_Système de Référence Altimétrique_INFÉRIEUR - NIVEAU: Niveau 2 (Niveau 2 13545); delta: 10 cm; sous Niveau: <aucun>
IFC_Pset_Données Métré - Surface 1re Menuiserie: 20400 cm2; Surface Vitre 1re Menuiserie: 13300 cm2; Surface du Cadre de la 1re Menuiserie: 7100 cm2; Surface 2e Menuiserie: 0 cm2; Surface Vitre 2e Menuiserie: 0 cm2; Surface du Cadre de la 2ème Menuiserie: 0 cm2; Surface de l'Ouverture: 20400 cm2; Surface de l'Ébrasement: 0 cm2; Surface du Seuil: 0 cm2; Surface du Seuil intérieur: 0 cm2; Volume du seuil: 0 cm3; Volume du seuil intérieur: 0 cm3; Surface de la Grille: 0 cm2; Volume de la Grille: 0 cm3
IFC_Pset_Matériaux_1° MENUISERIE - Cadre externe: Gris lumière; Verre: Transparent
Pset_WindowCommon - Reference: Fn 1 montant fixe 2 vitres ép 90 (..\Menuiserie classique\Fenêtre et Balcon\) <aucun>

# IfcWindow: Imposte fixe+1 imposte bas + arc haut (2)
In: Rez-de-Jardin
Type - ParameterTakesPrecedence: no; Sizeable: no; Material: Transparent, Blanc trafic, Rouge brillant
Type - IfcWindowLiningProperties - LiningDepth: 6 cm; LiningThickness: 4 cm
Type - IfcWindowPanelProperties - OperationType: FIXEDCASEMENT; FrameDepth: 6 cm; FrameThickness: 4 cm
Description: Fenêtre
__RECOGNIZE__ - TPLG: 101; TPLG_OD: 9004; GENERATE: 1
CTLG_EXTERNAL_LINK - 0, DocType: 3; 0, Tag: 100; 0, Crc: -1717521153; 1, DocType: 2; 1, Tag: 0; 1, Crc: -746779066; 2, DocType: 2; 2, Tag: 102; 2, Crc: 1680698050; 3, DocType: 2; 3, Tag: 103; 3, Crc: -848491367; 4, DocType: 2; 4, Tag: 104; 4, Crc: -623492449; 5, DocType: 2; 5, Tag: 105; 5, Crc: -848491367
IFC_PSET_PolygonOffset - polygonOffsetFactor: 2; polygonOffsetUnits: 2
IFC_Pset_Caractéristiques - Numéro niveau: 02; Titre niveau: Rez-de-Jardin; Modèle 1re menuiserie: Imposte fixe+1 imposte bas + arc haut
IFC_Pset_Géométrie_Allège - Hauteur: 0 cm; Stratigraphie: ...; Épaisseur: 0 cm
IFC_Pset_Géométrie_Ébrasement - Présent: no; Côté supérieur: no; Côté INFÉRIEUR: no; Épaisseur extérieure: 0 cm; Épaisseur latérale gauche: 0 cm; Épaisseur latérale droite: 0 cm; Épiasseur latérale supérieure: 0 cm; Épaisseur diagonale gauche: 0 cm; Épaisseur diagonale droite: 0 cm; Épaisseur diagonale inférieure: 0 cm; Épaisseur diagonale supérieure: 0 cm; Épaisseur intérieur: 0 cm
IFC_Pset_Géométrie_Seuil - Type: Aucun; Épaisseur: 0 cm; Épaisseur interne: 0 cm; Décalage séparation: 0 cm; Appui extérieur: 0 cm; Appui intérieur: 0 cm; Côté latéral externe: 0 cm; Côté latéral interne: 0 cm
IFC_Pset_Géométrie_Chambranle - Position: Aucun; Épaisseur Chambranle intérieur: 0 cm; Longueur Chambranle intérieur: 0 cm; Superposition Chambranle intérieur: 0 cm; Épaisseur Intrados: 0 cm; Épaisseur Chambranle extérieur: 0 cm; Largeur Chambranle extérieur: 0 cm; Superposition Chambranle extérieur: 0 cm; Épaisseur Intrados extérieur: 0 cm
IFC_Pset_Géométrie_CORNICHE depuis profil - Position: Aucune; sets with these values: 2
IFC_Pset_Géométrie_CORNICHE Extérieure à partir d'un profil - Décalage: 0; Angle: 0 deg; Symétrie: no; Fermer: no; sets with these values: 2
IFC_Pset_Géométrie_BASE Extérieure à partir d'un profil - Angle: 0 deg; Symétrie: no; Côté: 0 cm; sets with these values: 2
IFC_Pset_Géométrie_1° MENUISERIE - Position: Extérieur; Décalage: 0 cm
IFC_Pset_Géométrie_2° MENUISERIE - Décalage: 0 cm
IFC_Pset_Géométrie - Côté extérieur: 0; Invertir (dte/gche): no; Invertir (intérieur/extérieur): no; Hauteur: 217 cm; Hauteur 2: 0 cm; Rayon Cercle: 0 cm; Demi-axe horizontal: 0 cm; Demi-axe vertical: 0 cm
IFC_Pset_Géométrie_GRILLE - décalage: 0 cm; Offset latéral: 0 cm; Décalage supérieur: 0 cm; Décalage inférieur: 0 cm; Nombre accrochages latéraux: 0; Nombre d'accrochages supérieurs: 0; Nombre accrochages inférieurs: 0
IFC_Pset_Système de Référence Altimétrique_INFÉRIEUR - NIVEAU: Rez-de-Jardin (Rez-de-Jardin 15545); sous Niveau: <aucun>
IFC_Pset_Données Métré - Surface du Cadre de la 1re Menuiserie: 6500 cm2; Surface 2e Menuiserie: 0 cm2; Surface Vitre 2e Menuiserie: 0 cm2; Surface du Cadre de la 2ème Menuiserie: 0 cm2; Surface de l'Ébrasement: 0 cm2; Surface du Seuil: 0 cm2; Surface du Seuil intérieur: 0 cm2; Volume du seuil: 0 cm3; Volume du seuil intérieur: 0 cm3; Surface de la Grille: 0 cm2; Volume de la Grille: 0 cm3
IFC_Pset_Matériaux_1° MENUISERIE - Cadre interne: Blanc trafic; Cadre externe: Rouge brillant; Verre: Transparent; Panneau extérieur: Blanc trafic
Pset_WindowCommon - Reference: Imposte fixe+1 imposte bas + arc haut (..\projekt\) <aucun>
Name | OverallHeight (cm) | OverallWidth (cm) = Largeur (cm) | __RECOGNIZE__, ID = IFC_Pset_Caractéristiques, ID | Numérotation | Rayon Arc (cm) | delta (cm) | Surface 1re Menuiserie (cm2) = Surface de l'Ouverture (cm2) | Surface Vitre 1re Menuiserie (cm2)
Fenêtre 74100 | 226.703 | 98 | 74100 | 023 | 9.70297 | 1.7118 | 21900 | 9400
Fenêtre 74098 | 227 | 101 | 74098 | 022 | 10 | 1.60308 | 22600 | 9800
